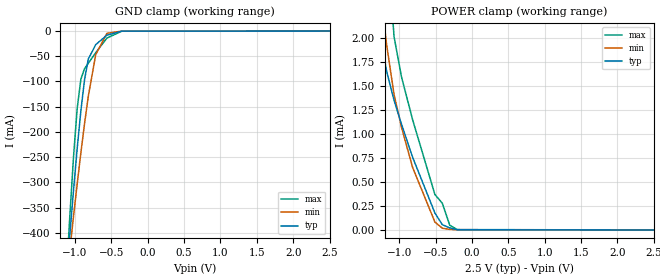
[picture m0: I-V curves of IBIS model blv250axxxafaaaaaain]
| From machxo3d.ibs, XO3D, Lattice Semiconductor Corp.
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|   Model blv250axxxafaaaaaain
[Model] blv250axxxafaaaaaain
Model_type Input
Polarity   Non-Inverting
Enable   Active-High
Vinl =  1.150V
Vinh =  1.350V
C_comp   4.200pF   3.800pF   7.500pF
[Temperature Range]   25.000   0.105k   -40.000
[Voltage Range]   2.500V   2.380V   2.630V
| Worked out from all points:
|   GND clamp passes 1 mA (typ) near -0.43 V on its own axis
|   POWER clamp passes 1 mA (typ) near -0.92 V on its own axis
[GND_clamp]
|Voltage   I(typ)   I(min)   I(max)
-2.5V     -3.262A    -2.545A    -4.485A
-1.123V   -498.5mA   -505.1mA   -498.3mA
-1.072V   -406.1mA   -436mA     -369.4mA
-1.021V   -317.1mA   -368.7mA   -251mA
-970mV    -233.3mA   -303.5mA   -153.4mA
-919mV    -157.7mA   -241.1mA   -95.21mA
-868mV    -95.78mA   -182.7mA   -74.26mA
-817mV    -55.48mA   -129.4mA   -63.96mA
-715mV    -26.89mA   -46.57mA   -42.82mA
-562mV    -8.195mA   -4.484mA   -13.98mA
-358mV    -153.4uA   -68.26uA   -250.2uA
2.5V      0A         0A         0A
[POWER_clamp]
|Voltage   I(typ)   I(min)   I(max)
-2.5V     19.37mA    14.08mA    35.47mA
-1.274V   2.185mA    2.634mA    5.424mA
-1.223V   1.865mA    2.265mA    4.051mA
-1.172V   1.654mA    1.93mA     3.052mA
-1.07V    1.353mA    1.412mA    2.016mA
-968mV    1.104mA    1.071mA    1.597mA
-815mV    758.5uA    651.8uA    1.15mA
-509mV    176.7uA    82.75uA    370.5uA
-407mV    55.24uA    18.01uA    278.8uA
-305mV    21.57uA    6.5uA      49.89uA
-203mV    2.401uA    2.25uA     4.21uA
2.5V      0A         0A         3.059nA
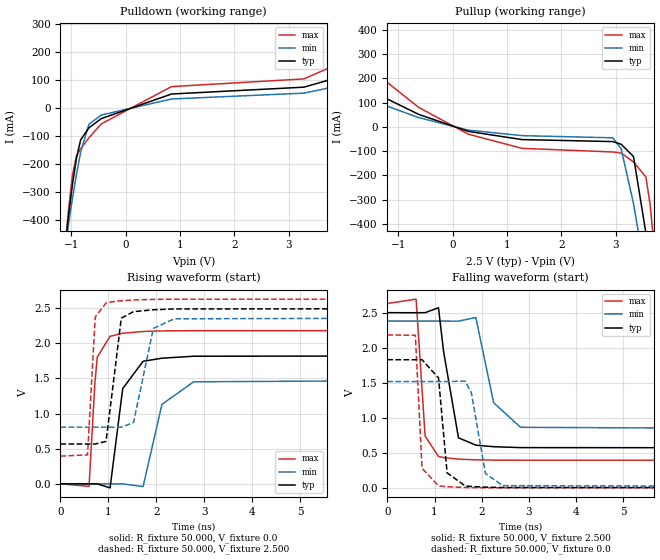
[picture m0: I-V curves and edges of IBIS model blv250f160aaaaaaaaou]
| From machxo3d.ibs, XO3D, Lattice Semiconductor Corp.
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|   Model blv250f160aaaaaaaaou
[Model] blv250f160aaaaaaaaou
Model_type Output
Polarity   Non-Inverting
Enable   Active-High
Vmeas =  1.250V
Cref =  3.000pF
Rref =  50.000
Vref =  1.250V
C_comp   4.200pF   3.800pF   7.500pF
[Temperature Range]   25.000   0.105k   -40.000
[Voltage Range]   2.500V   2.380V   2.630V
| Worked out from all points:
|   slope of the pulldown table from 0 to 0.375 V, typ, clamps not added: 13.6 ohm
|   slope of the pullup table from 0 to 0.375 V, typ, clamps not added: 16.3 ohm
|   rising waveform, R_fixture 50.000, V_fixture 0.0: 20-80 % time 206ps typ, 326ps min, 111ps max; typ from 0 V to 1.83 V
|   rising waveform, R_fixture 50.000, V_fixture 2.500: 20-80 % time 152ps typ, 261ps min, 82.5ps max; typ from 0.567 V to 2.5 V
|   falling waveform, R_fixture 50.000, V_fixture 2.500: 20-80 % time 196ps typ, 321ps min, 119ps max; typ from 2.5 V to 0.567 V
|   falling waveform, R_fixture 50.000, V_fixture 0.0: 20-80 % time 127ps typ, 212ps min, 78.8ps max; typ from 1.83 V to 0 V
[Pulldown]
|Voltage   I(typ)   I(min)   I(max)
-2.5V     -3.263A    -2.546A    -4.487A
-1.132V   -524.4mA   -522.1mA   -541.9mA
-1.056V   -391.7mA   -420.6mA   -371.7mA
-980mV    -273mA     -323.8mA   -240.3mA
-904mV    -177.6mA   -234.6mA   -169.5mA
-828mV    -113.5mA   -157.4mA   -146mA
-676mV    -70.67mA   -57.86mA   -106.2mA
-448mV    -37.92mA   -25.21mA   -56.63mA
844mV     49.74mA    32.02mA    76.15mA
3.276V    74.1mA     52.77mA    103.6mA
4.188V    124.4mA    89.67mA    180.5mA
5V        189.3mA    133.3mA    285.6mA
[Pullup]
|Voltage   I(typ)   I(min)   I(max)
-2.5V     258.3mA    191.7mA    416mA
-624mV    51.9mA     38.54mA    80.72mA
288mV     -18.29mA   -13.09mA   -29.66mA
1.276V    -52.17mA   -35.9mA    -88.36mA
2.948V    -60.45mA   -44.87mA   -103.4mA
3.1V      -71.47mA   -89.87mA   -107.6mA
3.328V    -122.2mA   -316.8mA   -144.4mA
3.556V    -438.5mA   -619.2mA   -206.7mA
3.632V    -576mA     -726.1mA   -318mA
3.708V    -718.7mA   -834.7mA   -491.1mA
3.784V    -864.6mA   -944.6mA   -687mA
5V        -3.326A    -2.771A    -4.212A
[Ramp]
| variable   typ   min   max
dV/dt_r   1.097/0.206n   0.910/0.325n   1.309/0.110n
dV/dt_f   1.160/0.196n   0.944/0.320n   1.341/0.119n
R_load = 50.000
[Rising Waveform]
R_fixture= 50.000
V_fixture= 0.0
V_fixture_min= 0.0
V_fixture_max= 0.0
|time   V(typ)   V(min)   V(max)
0s        6.258nV    42.73nV    18.47nV
597ps     -200.6uV   920.1nV    -35.25mV
718ps     -428.8uV   920.1nV    1.422V
769ps     -516.5uV   920.1nV    1.805V
1.036ns   -57.26mV   -22.87uV   2.101V
1.3ns     1.356V     -654.9uV   2.144V
1.725ns   1.745V     -39mV      2.169V
2.119ns   1.789V     1.132V     2.177V
2.781ns   1.817V     1.453V     2.181V
20ns      1.829V     1.517V     2.182V
[Rising Waveform]
R_fixture= 50.000
V_fixture= 2.500
V_fixture_min= 2.380
V_fixture_max= 2.630
|time   V(typ)   V(min)   V(max)
0s        567.4mV    806.9mV    394.6mV
565ps     567.2mV    806.9mV    412.4mV
727ps     567mV      806.9mV    2.377V
951ps     604.4mV    806.7mV    2.574V
1.068ns   1.238V     806.2mV    2.591V
1.27ns    2.359V     806.8mV    2.607V
1.525ns   2.452V     871.4mV    2.618V
1.939ns   2.478V     2.213V     2.626V
2.376ns   2.49V      2.35V      2.629V
20ns      2.5V       2.38V      2.63V
[Falling Waveform]
R_fixture= 50.000
V_fixture= 2.500
V_fixture_min= 2.380
V_fixture_max= 2.630
|time   V(typ)   V(min)   V(max)
0s        2.5V       2.38V      2.63V
610ps     2.499V     2.38V      2.693V
801ps     2.5V       2.38V      738.5mV
1.084ns   2.57V      2.38V      448mV
1.192ns   1.947V     2.38V      432.3mV
1.508ns   714mV      2.379V     410mV
1.876ns   609.5mV    2.431V     399.7mV
2.253ns   587.2mV    1.214V     396.2mV
2.823ns   574.3mV    864.2mV    394.9mV
20ns      567.3mV    806.9mV    394.5mV
[Falling Waveform]
R_fixture= 50.000
V_fixture= 0.0
V_fixture_min= 0.0
V_fixture_max= 0.0
|time   V(typ)   V(min)   V(max)
0s        1.829V     1.517V     2.182V
594ps     1.828V     1.517V     2.177V
736ps     1.829V     1.517V     278.8mV
1.085ns   1.568V     1.517V     29.01mV
1.267ns   213.9mV    1.517V     15.96mV
1.649ns   28.04mV    1.523V     5.319mV
1.782ns   19.34mV    1.354V     3.815mV
2.078ns   10.17mV    205.1mV    1.609mV
2.445ns   5.144mV    31.58mV    507.2uV
20ns      -109.5nV   -67.12nV   -21.07nV
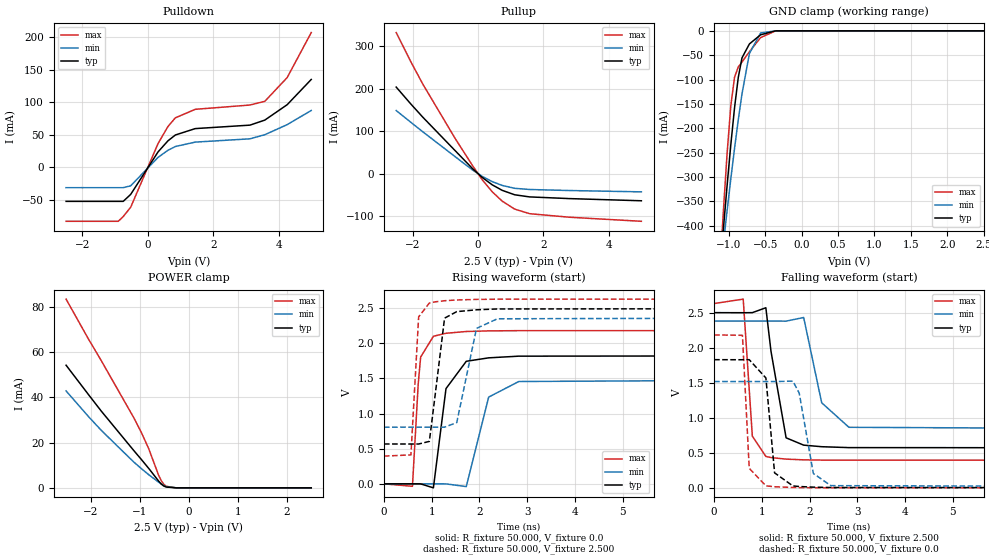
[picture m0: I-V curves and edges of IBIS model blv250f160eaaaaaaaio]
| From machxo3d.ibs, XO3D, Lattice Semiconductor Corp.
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|   Model blv250f160eaaaaaaaio
[Model] blv250f160eaaaaaaaio
Model_type I/O
Polarity   Non-Inverting
Enable   Active-Low
Vinl =  1.150V
Vinh =  1.350V
Vmeas =  1.250V
Cref =  3.000pF
Rref =  50.000
Vref =  1.250V
C_comp   4.200pF   3.800pF   7.500pF
[Temperature Range]   25.000   0.105k   -40.000
[Voltage Range]   2.500V   2.380V   2.630V
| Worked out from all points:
|   slope of the pulldown table from 0 to 0.375 V, typ, clamps not added: 13.6 ohm
|   slope of the pullup table from 0 to 0.375 V, typ, clamps not added: 16.3 ohm
|   GND clamp passes 1 mA (typ) near -0.43 V on its own axis
|   POWER clamp passes 1 mA (typ) near -0.52 V on its own axis
|   rising waveform, R_fixture 50.000, V_fixture 0.0: 20-80 % time 206ps typ, 326ps min, 111ps max; typ from 0 V to 1.83 V
|   rising waveform, R_fixture 50.000, V_fixture 2.500: 20-80 % time 152ps typ, 261ps min, 82.5ps max; typ from 0.567 V to 2.5 V
|   falling waveform, R_fixture 50.000, V_fixture 2.500: 20-80 % time 196ps typ, 321ps min, 119ps max; typ from 2.5 V to 0.567 V
|   falling waveform, R_fixture 50.000, V_fixture 0.0: 20-80 % time 127ps typ, 212ps min, 78.8ps max; typ from 1.83 V to 0 V
[Pulldown]
|Voltage   I(typ)   I(min)   I(max)
-2.5V     -52.31mA   -31.26mA   -82.98mA
-904mV    -52.31mA   -31.26mA   -82.98mA
-752mV    -52.31mA   -31.26mA   -75.68mA
-524mV    -41.64mA   -28.44mA   -61.36mA
312mV     23.61mA    15.21mA    36.41mA
616mV     40.73mA    26.21mA    62.71mA
844mV     49.74mA    32.02mA    76.15mA
1.452V    59.56mA    38.79mA    89.19mA
3.124V    64.87mA    43.83mA    95.79mA
3.58V     72.62mA    50.15mA    101.5mA
4.264V    96.31mA    65.66mA    138mA
5V        135.1mA    87.41mA    207.2mA
[Pullup]
|Voltage   I(typ)   I(min)   I(max)
-2.5V     204.1mA    148.8mA    332.6mA
-2.068V   165.6mA    122.1mA    266.1mA
-1.688V   133.3mA    98.85mA    211.4mA
-700mV    54.54mA    40.29mA    83.37mA
-168mV    12.23mA    8.92mA     19.44mA
136mV     -9.136mA   -6.562mA   -14.75mA
440mV     -26.35mA   -18.77mA   -42.94mA
744mV     -39.29mA   -27.7mA    -64.76mA
1.124V    -49.7mA    -34.48mA   -83.45mA
1.58V     -54.71mA   -37.23mA   -94.24mA
2.796V    -58.69mA   -39.68mA   -102.6mA
5V        -63.82mA   -42.81mA   -112.2mA
[GND_clamp]
|Voltage   I(typ)   I(min)   I(max)
-2.5V     -3.262A    -2.545A    -4.485A
-1.123V   -498.5mA   -505.1mA   -498.3mA
-1.072V   -406.1mA   -436mA     -369.4mA
-1.021V   -317.1mA   -368.7mA   -251mA
-970mV    -233.3mA   -303.5mA   -153.4mA
-919mV    -157.7mA   -241.1mA   -95.21mA
-868mV    -95.78mA   -182.7mA   -74.26mA
-817mV    -55.48mA   -129.4mA   -63.96mA
-715mV    -26.89mA   -46.57mA   -42.82mA
-562mV    -8.195mA   -4.484mA   -13.98mA
-358mV    -153.4uA   -68.26uA   -250.2uA
2.5V      0A         0A         0A
[POWER_clamp]
|Voltage   I(typ)   I(min)   I(max)
-2.5V     54.22mA    42.85mA    83.44mA
-2.039V   41.12mA    31.42mA    65.62mA
-1.784V   33.98mA    25.46mA    56.3mA
-1.121V   16.55mA    11.45mA    31.07mA
-968mV    12.63mA    8.576mA    24.62mA
-815mV    8.614mA    5.831mA    17.33mA
-611mV    2.953mA    2.495mA    5.465mA
-560mV    1.702mA    1.758mA    3.215mA
-509mV    833.1uA    1.093mA    1.608mA
-458mV    359uA      552.7uA    679.3uA
-254mV    7.444uA    6.928uA    15.57uA
2.5V      0A         0A         3.059nA
[Ramp]
| variable   typ   min   max
dV/dt_r   1.097/0.206n   0.910/0.325n   1.309/0.110n
dV/dt_f   1.160/0.196n   0.944/0.320n   1.341/0.119n
R_load = 50.000
[Rising Waveform]
R_fixture= 50.000
V_fixture= 0.0
V_fixture_min= 0.0
V_fixture_max= 0.0
|time   V(typ)   V(min)   V(max)
0s        6.258nV    42.86nV    18.47nV
597ps     -200.6uV   924.5nV    -35.25mV
718ps     -428.8uV   924.5nV    1.422V
769ps     -516.5uV   924.5nV    1.805V
1.036ns   -57.26mV   -22.86uV   2.101V
1.3ns     1.356V     -654.8uV   2.144V
1.725ns   1.745V     -39mV      2.169V
2.194ns   1.794V     1.235V     2.178V
2.825ns   1.818V     1.457V     2.181V
20ns      1.829V     1.517V     2.182V
[Rising Waveform]
R_fixture= 50.000
V_fixture= 2.500
V_fixture_min= 2.380
V_fixture_max= 2.630
|time   V(typ)   V(min)   V(max)
0s        567.4mV    806.9mV    394.6mV
565ps     567.2mV    806.9mV    412.4mV
727ps     567mV      806.9mV    2.377V
951ps     604.4mV    806.7mV    2.574V
1.068ns   1.238V     806.2mV    2.591V
1.27ns    2.359V     806.8mV    2.607V
1.525ns   2.452V     871.4mV    2.618V
1.939ns   2.478V     2.213V     2.626V
2.376ns   2.49V      2.35V      2.629V
20ns      2.5V       2.38V      2.63V
[Falling Waveform]
R_fixture= 50.000
V_fixture= 2.500
V_fixture_min= 2.380
V_fixture_max= 2.630
|time   V(typ)   V(min)   V(max)
0s        2.5V       2.38V      2.63V
610ps     2.499V     2.38V      2.693V
801ps     2.5V       2.38V      738.5mV
1.084ns   2.57V      2.38V      448mV
1.192ns   1.947V     2.38V      432.3mV
1.508ns   714mV      2.379V     410mV
1.876ns   609.5mV    2.431V     399.7mV
2.253ns   587.2mV    1.214V     396.2mV
2.823ns   574.3mV    864.2mV    394.9mV
20ns      567.3mV    806.9mV    394.5mV
[Falling Waveform]
R_fixture= 50.000
V_fixture= 0.0
V_fixture_min= 0.0
V_fixture_max= 0.0
|time   V(typ)   V(min)   V(max)
0s        1.829V     1.517V     2.182V
594ps     1.828V     1.517V     2.177V
736ps     1.829V     1.517V     278.8mV
1.085ns   1.568V     1.517V     29.01mV
1.267ns   213.9mV    1.517V     15.96mV
1.649ns   28.04mV    1.523V     5.319mV
1.782ns   19.34mV    1.354V     3.815mV
2.078ns   10.17mV    205.1mV    1.609mV
2.445ns   5.144mV    31.58mV    507.2uV
20ns      -109.5nV   -67.12nV   -21.07nV
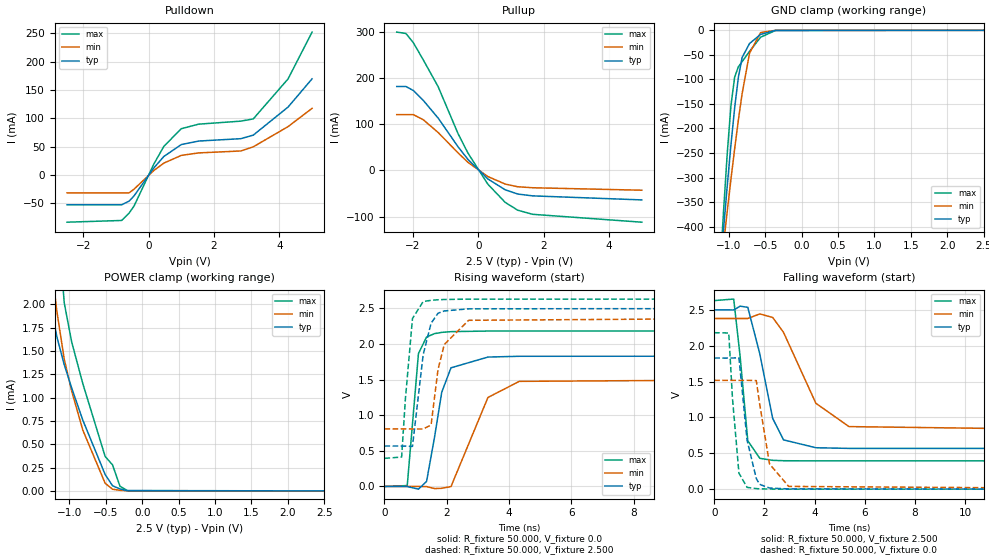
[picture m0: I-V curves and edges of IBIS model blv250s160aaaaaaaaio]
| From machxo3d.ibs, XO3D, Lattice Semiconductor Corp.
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|   Model blv250s160aaaaaaaaio
[Model] blv250s160aaaaaaaaio
Model_type I/O
Polarity   Non-Inverting
Enable   Active-Low
Vinl =  1.150V
Vinh =  1.350V
Vmeas =  1.250V
Cref =  3.000pF
Rref =  50.000
Vref =  1.250V
C_comp   4.200pF   3.800pF   7.500pF
[Temperature Range]   25.000   0.105k   -40.000
[Voltage Range]   2.500V   2.380V   2.630V
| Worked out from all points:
|   slope of the pulldown table from 0 to 0.375 V, typ, clamps not added: 13.6 ohm
|   slope of the pullup table from 0 to 0.375 V, typ, clamps not added: 16.3 ohm
|   GND clamp passes 1 mA (typ) near -0.43 V on its own axis
|   POWER clamp passes 1 mA (typ) near -0.92 V on its own axis
|   rising waveform, R_fixture 50.000, V_fixture 0.0: 20-80 % time 428ps typ, 783ps min, 212ps max; typ from 0 V to 1.83 V
|   rising waveform, R_fixture 50.000, V_fixture 2.500: 20-80 % time 387ps typ, 428ps min, 242ps max; typ from 0.567 V to 2.5 V
|   falling waveform, R_fixture 50.000, V_fixture 2.500: 20-80 % time 674ps typ, 1.31ns min, 338ps max; typ from 2.5 V to 0.567 V
|   falling waveform, R_fixture 50.000, V_fixture 0.0: 20-80 % time 439ps typ, 471ps min, 277ps max; typ from 1.83 V to 0 V
[Pulldown]
|Voltage   I(typ)   I(min)   I(max)
-2.5V     -52.31mA   -31.26mA   -82.98mA
-828mV    -52.31mA   -31.26mA   -79.94mA
-600mV    -45.86mA   -31.26mA   -66.93mA
-448mV    -36.56mA   -24.66mA   -54.4mA
160mV     12.89mA    8.306mA    19.88mA
464mV     32.88mA    21.18mA    50.69mA
996mV     53.81mA    34.73mA    81.8mA
1.528V    60.05mA    39.14mA    89.82mA
2.82V     64.22mA    42.56mA    95.13mA
3.2V      70.47mA    49.87mA    99.09mA
4.264V    119.9mA    85.45mA    169.5mA
5V        169.7mA    117.7mA    252.1mA
[Pullup]
|Voltage   I(typ)   I(min)   I(max)
-2.5V     182.4mA    121.2mA    300.4mA
-2.22V    182.4mA    121.2mA    297.4mA
-1.992V   173.6mA    121.2mA    277.4mA
-1.688V   152.2mA    110.2mA    240.1mA
-1.232V   113.7mA    82.42mA    181.8mA
-624mV    51.53mA    38.3mA     80.07mA
-320mV    23.99mA    17.67mA    37.75mA
288mV     -18.29mA   -13.09mA   -29.66mA
820mV     -41.87mA   -29.44mA   -69.24mA
1.2V      -51.05mA   -35.28mA   -86.08mA
1.656V    -55.06mA   -37.43mA   -95.07mA
5V        -63.82mA   -42.81mA   -112.2mA
[GND_clamp]
|Voltage   I(typ)   I(min)   I(max)
-2.5V     -3.262A    -2.545A    -4.485A
-1.123V   -498.5mA   -505.1mA   -498.3mA
-1.072V   -406.1mA   -436mA     -369.4mA
-1.021V   -317.1mA   -368.7mA   -251mA
-970mV    -233.3mA   -303.5mA   -153.4mA
-919mV    -157.7mA   -241.1mA   -95.21mA
-868mV    -95.78mA   -182.7mA   -74.26mA
-817mV    -55.48mA   -129.4mA   -63.96mA
-715mV    -26.89mA   -46.57mA   -42.82mA
-562mV    -8.195mA   -4.484mA   -13.98mA
-358mV    -153.4uA   -68.26uA   -250.2uA
2.5V      0A         0A         0A
[POWER_clamp]
|Voltage   I(typ)   I(min)   I(max)
-2.5V     19.37mA    14.08mA    35.47mA
-1.274V   2.185mA    2.634mA    5.424mA
-1.223V   1.865mA    2.265mA    4.051mA
-1.172V   1.654mA    1.93mA     3.052mA
-1.07V    1.353mA    1.412mA    2.016mA
-968mV    1.104mA    1.071mA    1.597mA
-815mV    758.5uA    651.8uA    1.15mA
-509mV    176.7uA    82.75uA    370.5uA
-407mV    55.24uA    18.01uA    278.8uA
-305mV    21.57uA    6.5uA      49.89uA
-203mV    2.401uA    2.25uA     4.21uA
2.5V      0A         0A         3.059nA
[Ramp]
| variable   typ   min   max
dV/dt_r   1.097/0.427n   0.910/0.781n   1.309/0.212n
dV/dt_f   1.160/0.674n   0.944/1.308n   1.341/0.338n
R_load = 50.000
[Rising Waveform]
R_fixture= 50.000
V_fixture= 0.0
V_fixture_min= 0.0
V_fixture_max= 0.0
|time   V(typ)   V(min)   V(max)
0s        6.258nV    42.67nV    18.47nV
731ps     -485.9uV   576.8nV    12.5mV
1.091ns   -38.02mV   -270.6uV   1.865V
1.352ns   70.76mV    -1.671mV   2.098V
1.607ns   689.8mV    -29.61mV   2.145V
1.839ns   1.323V     -26.03mV   2.162V
2.136ns   1.665V     -1.426mV   2.173V
3.323ns   1.816V     1.249V     2.181V
4.329ns   1.827V     1.475V     2.182V
20ns      1.829V     1.517V     2.182V
[Rising Waveform]
R_fixture= 50.000
V_fixture= 2.500
V_fixture_min= 2.380
V_fixture_max= 2.630
|time   V(typ)   V(min)   V(max)
0s        567.4mV    806.9mV    394.6mV
551ps     567.3mV    806.9mV    412.3mV
670ps     566.6mV    806.9mV    1.219V
899ps     562.6mV    806.9mV    2.358V
1.242ns   1.848V     806.7mV    2.594V
1.497ns   2.291V     862.1mV    2.613V
1.719ns   2.431V     1.642V     2.62V
1.921ns   2.463V     1.993V     2.624V
2.704ns   2.493V     2.332V     2.629V
20ns      2.5V       2.38V      2.63V
[Falling Waveform]
R_fixture= 50.000
V_fixture= 2.500
V_fixture_min= 2.380
V_fixture_max= 2.630
|time   V(typ)   V(min)   V(max)
0s        2.5V       2.38V      2.63V
777ps     2.499V     2.38V      2.651V
1.033ns   2.552V     2.38V      1.852V
1.338ns   2.536V     2.38V      675mV
1.817ns   1.887V     2.444V     430.3mV
2.328ns   988.7mV    2.395V     402.3mV
2.76ns    687.8mV    2.188V     396.6mV
4.05ns    577.7mV    1.198V     394.5mV
5.369ns   568.6mV    872.5mV    394.4mV
20ns      567.4mV    806.8mV    394.4mV
[Falling Waveform]
R_fixture= 50.000
V_fixture= 0.0
V_fixture_min= 0.0
V_fixture_max= 0.0
|time   V(typ)   V(min)   V(max)
0s        1.829V     1.517V     2.182V
580ps     1.828V     1.517V     2.178V
729ps     1.829V     1.517V     1.263V
986ps     1.833V     1.517V     224.2mV
1.31ns    684.8mV    1.518V     24.95mV
1.676ns   148.8mV    1.514V     7.802mV
1.811ns   67.29mV    1.187V     5.421mV
2.205ns   15.76mV    351.1mV    1.759mV
2.967ns   3.493mV    38.31mV    223.7uV
20ns      26.49nV    97.26nV    83.58nV
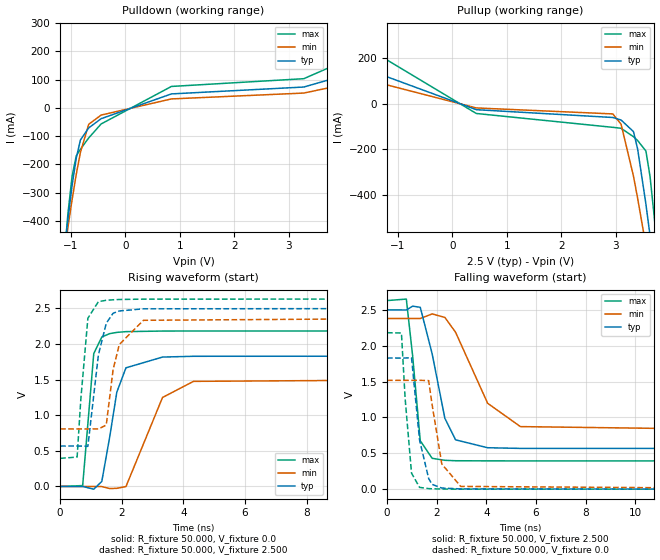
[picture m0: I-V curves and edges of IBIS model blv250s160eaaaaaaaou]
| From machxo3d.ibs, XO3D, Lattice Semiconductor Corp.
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|   Model blv250s160eaaaaaaaou
[Model] blv250s160eaaaaaaaou
Model_type Output
Polarity   Non-Inverting
Enable   Active-High
Vmeas =  1.250V
Cref =  3.000pF
Rref =  50.000
Vref =  1.250V
C_comp   4.200pF   3.800pF   7.500pF
[Temperature Range]   25.000   0.105k   -40.000
[Voltage Range]   2.500V   2.380V   2.630V
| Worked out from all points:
|   slope of the pulldown table from 0 to 0.375 V, typ, clamps not added: 13.6 ohm
|   slope of the pullup table from 0 to 0.375 V, typ, clamps not added: 16.3 ohm
|   rising waveform, R_fixture 50.000, V_fixture 0.0: 20-80 % time 428ps typ, 783ps min, 212ps max; typ from 0 V to 1.83 V
|   rising waveform, R_fixture 50.000, V_fixture 2.500: 20-80 % time 387ps typ, 428ps min, 243ps max; typ from 0.567 V to 2.5 V
|   falling waveform, R_fixture 50.000, V_fixture 2.500: 20-80 % time 674ps typ, 1.31ns min, 338ps max; typ from 2.5 V to 0.567 V
|   falling waveform, R_fixture 50.000, V_fixture 0.0: 20-80 % time 439ps typ, 471ps min, 277ps max; typ from 1.83 V to 0 V
[Pulldown]
|Voltage   I(typ)   I(min)   I(max)
-2.5V     -3.263A    -2.546A    -4.487A
-1.132V   -524.4mA   -522.1mA   -541.9mA
-1.056V   -391.7mA   -420.6mA   -371.7mA
-980mV    -273mA     -323.8mA   -240.3mA
-904mV    -177.6mA   -234.6mA   -169.5mA
-828mV    -113.5mA   -157.4mA   -146mA
-676mV    -70.67mA   -57.86mA   -106.2mA
-448mV    -37.92mA   -25.21mA   -56.63mA
844mV     49.74mA    32.02mA    76.15mA
3.276V    74.1mA     52.77mA    103.6mA
4.188V    124.4mA    89.63mA    180.5mA
5V        189.1mA    133.2mA    285.3mA
[Pullup]
|Voltage   I(typ)   I(min)   I(max)
-2.5V     198.2mA    130.5mA    332.2mA
-1.992V   186.5mA    130.1mA    303.4mA
440mV     -26.35mA   -18.77mA   -42.94mA
2.948V    -60.45mA   -44.87mA   -103.4mA
3.1V      -71.47mA   -89.87mA   -107.6mA
3.328V    -122.2mA   -316.8mA   -144.4mA
3.404V    -198.1mA   -413.3mA   -161mA
3.556V    -438.5mA   -619.2mA   -206.7mA
3.632V    -576mA     -726.1mA   -318mA
3.708V    -718.7mA   -834.7mA   -491.1mA
3.784V    -864.6mA   -944.6mA   -687mA
5V        -3.326A    -2.771A    -4.212A
[Ramp]
| variable   typ   min   max
dV/dt_r   1.097/0.427n   0.910/0.781n   1.309/0.212n
dV/dt_f   1.160/0.674n   0.944/1.308n   1.341/0.338n
R_load = 50.000
[Rising Waveform]
R_fixture= 50.000
V_fixture= 0.0
V_fixture_min= 0.0
V_fixture_max= 0.0
|time   V(typ)   V(min)   V(max)
0s        6.258nV    42.67nV    18.47nV
731ps     -485.9uV   577.8nV    12.5mV
1.091ns   -38.02mV   -270.6uV   1.865V
1.352ns   70.76mV    -1.671mV   2.098V
1.607ns   689.8mV    -29.34mV   2.145V
1.839ns   1.323V     -26.03mV   2.162V
2.136ns   1.665V     -1.426mV   2.173V
3.323ns   1.816V     1.249V     2.181V
4.329ns   1.827V     1.475V     2.182V
20ns      1.829V     1.517V     2.182V
[Rising Waveform]
R_fixture= 50.000
V_fixture= 2.500
V_fixture_min= 2.380
V_fixture_max= 2.630
|time   V(typ)   V(min)   V(max)
0s        567.4mV    806.9mV    394.6mV
551ps     567.3mV    806.9mV    412.3mV
670ps     566.6mV    806.9mV    1.219V
900ps     563.1mV    806.9mV    2.361V
1.242ns   1.848V     806.7mV    2.594V
1.497ns   2.291V     862.1mV    2.613V
1.719ns   2.431V     1.642V     2.62V
1.921ns   2.463V     1.993V     2.624V
2.704ns   2.493V     2.332V     2.629V
20ns      2.5V       2.38V      2.63V
[Falling Waveform]
R_fixture= 50.000
V_fixture= 2.500
V_fixture_min= 2.380
V_fixture_max= 2.630
|time   V(typ)   V(min)   V(max)
0s        2.5V       2.38V      2.63V
777ps     2.499V     2.38V      2.651V
1.033ns   2.552V     2.38V      1.852V
1.338ns   2.536V     2.38V      675mV
1.817ns   1.887V     2.444V     430.3mV
2.328ns   988.7mV    2.395V     402.3mV
2.76ns    687.8mV    2.188V     396.6mV
4.05ns    577.7mV    1.198V     394.5mV
5.369ns   568.6mV    872.5mV    394.4mV
20ns      567.4mV    806.8mV    394.4mV
[Falling Waveform]
R_fixture= 50.000
V_fixture= 0.0
V_fixture_min= 0.0
V_fixture_max= 0.0
|time   V(typ)   V(min)   V(max)
0s        1.829V     1.517V     2.182V
580ps     1.828V     1.517V     2.178V
729ps     1.829V     1.517V     1.263V
986ps     1.833V     1.517V     224.2mV
1.31ns    684.8mV    1.518V     24.95mV
1.676ns   148.8mV    1.514V     7.802mV
1.811ns   67.29mV    1.187V     5.421mV
2.205ns   15.76mV    351.1mV    1.759mV
2.967ns   3.493mV    38.31mV    223.7uV
20ns      26.49nV    97.26nV    83.58nV
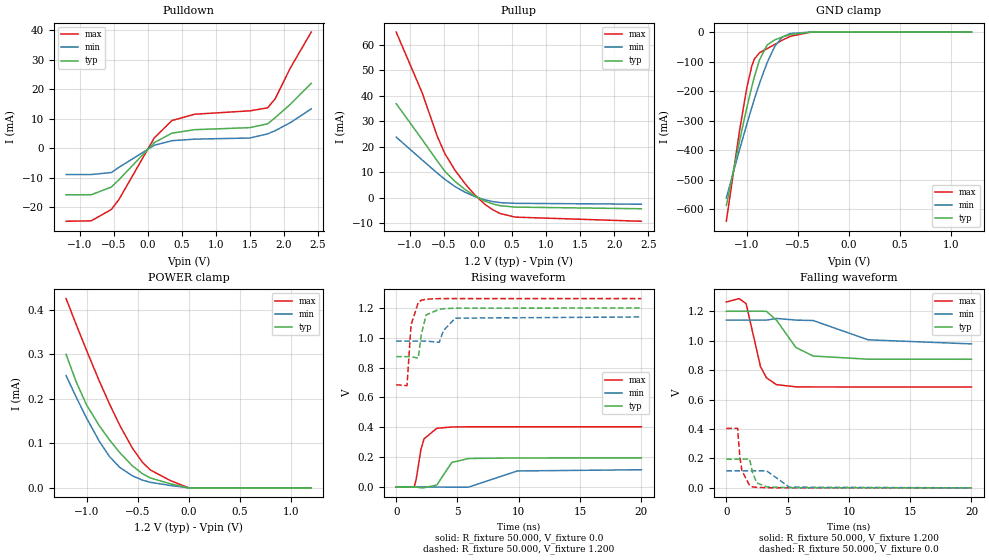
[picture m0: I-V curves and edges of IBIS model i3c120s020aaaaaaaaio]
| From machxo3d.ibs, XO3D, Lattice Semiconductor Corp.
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|   Model i3c120s020aaaaaaaaio
[Model] i3c120s020aaaaaaaaio
Model_type I/O
Polarity   Non-Inverting
Enable   Active-Low
Vinl =  0.420V
Vinh =  0.780V
Vmeas =  0.600V
Cref =  0.0F
Rref =  1.000M
Vref =  0.0V
C_comp   4.200pF   3.800pF   7.500pF
[Temperature Range]   25.000   0.105k   -40.000
[Voltage Range]   1.200V   1.140V   1.260V
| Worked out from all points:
|   slope of the pulldown table from 0 to 0.18 V, typ, clamps not added: 55.1 ohm
|   slope of the pullup table from 0 to 0.18 V, typ, clamps not added: 85.3 ohm
|   GND clamp passes 1 mA (typ) near -0.44 V on its own axis
|   rising waveform, R_fixture 50.000, V_fixture 0.0: 20-80 % time 910ps typ, 1.64ns min, 583ps max; typ from 0 V to 0.195 V
|   rising waveform, R_fixture 50.000, V_fixture 1.200: 20-80 % time 368ps typ, 414ps min, 384ps max; typ from 0.874 V to 1.2 V
|   falling waveform, R_fixture 50.000, V_fixture 1.200: 20-80 % time 1.84ns typ, 3.15ns min, 991ps max; typ from 1.2 V to 0.874 V
|   falling waveform, R_fixture 50.000, V_fixture 0.0: 20-80 % time 404ps typ, 468ps min, 389ps max; typ from 0.195 V to 0 V
[Pulldown]
|Voltage   I(typ)   I(min)   I(max)
-1.2V     -15.77mA   -8.921mA   -24.76mA
-830mV    -15.77mA   -8.921mA   -24.61mA
-534mV    -13.14mA   -8.234mA   -20.74mA
-423mV    -10.67mA   -6.463mA   -17.35mA
95mV      1.91mA     997.3uA    3.496mA
354mV     5.095mA    2.558mA    9.38mA
687mV     6.287mA    3.08mA     11.52mA
1.501V    6.983mA    3.463mA    12.68mA
1.76V     8.276mA    4.869mA    13.69mA
1.871V    10.37mA    5.955mA    16.78mA
2.093V    14.88mA    8.68mA     27.18mA
2.4V      22.01mA    13.33mA    39.38mA
[Pullup]
|Voltage   I(typ)   I(min)   I(max)
-1.2V     36.87mA    23.76mA    64.96mA
-819mV    22.8mA     14.8mA     41.13mA
-597mV    14.41mA    9.656mA    24.1mA
-486mV    10.37mA    7.225mA    17.3mA
-338mV    6.412mA    4.38mA     10.82mA
-190mV    3.229mA    2.154mA    5.518mA
-42mV     628.1uA    407.3uA    979.6uA
106mV     -1.356mA   -861.5uA   -2.669mA
217mV     -2.425mA   -1.522mA   -4.729mA
328mV     -3.145mA   -1.941mA   -6.218mA
550mV     -3.688mA   -2.208mA   -7.621mA
2.4V      -4.336mA   -2.551mA   -9.246mA
[GND_clamp]
|Voltage   I(typ)   I(min)   I(max)
-1.2V     -586.8mA   -561.6mA   -640.3mA
-1.075V   -375.3mA   -403.2mA   -342.9mA
-1V       -256.8mA   -312.3mA   -188.8mA
-950mV    -184.3mA   -254.5mA   -114mA
-925mV    -151.1mA   -226.6mA   -91.27mA
-875mV    -93.95mA   -173.6mA   -70mA
-800mV    -43.51mA   -102.9mA   -56.05mA
-725mV    -26.4mA    -48.03mA   -41.58mA
-650mV    -16.51mA   -16.35mA   -27.17mA
-575mV    -8.674mA   -5.016mA   -14.71mA
-375mV    -194.8uA   -87.66uA   -296.2uA
1.2V      -42.59nA   0A         -5.33uA
[POWER_clamp]
|Voltage   I(typ)   I(min)   I(max)
-1.2V     299.6uA    251.9uA    424.8uA
-1.1V     237.3uA    203.2uA    366uA
-1V       186.4uA    156.9uA    308.7uA
-875mV    139.5uA    104.5uA    239.9uA
-775mV    107.7uA    70.18uA    188.3uA
-675mV    79.18uA    45.9uA     140.6uA
-550mV    49.19uA    26.84uA    88.83uA
-450mV    31.3uA     17.16uA    56.66uA
-375mV    22.16uA    12.38uA    40.11uA
-175mV    8.775uA    5.159uA    15.8uA
0V        3.648nA    7.361nA    0A
1.2V      0A         0A         0A
[Ramp]
| variable   typ   min   max
dV/dt_r   0.117/0.904n   69.347m/1.658n   0.242/0.588n
dV/dt_f   0.196/1.819n   97.061m/3.123n   0.345/0.973n
R_load = 50.000
[Rising Waveform]
R_fixture= 50.000
V_fixture= 0.0
V_fixture_min= 0.0
V_fixture_max= 0.0
|time   V(typ)   V(min)   V(max)
0s        284.9uV    165.7uV    490.2uV
1.467ns   305.6uV    180.4uV    1.089mV
1.625ns   -392.5uV   180.4uV    49.23mV
2.016ns   -5.636mV   205.4uV    251.4mV
2.27ns    -5.071mV   346.2uV    322.7mV
3.309ns   13.22mV    -248.4uV   393.4mV
4.532ns   164.3mV    -1.2mV     402.4mV
5.901ns   191.1mV    -859.4uV   403.6mV
9.887ns   194.8mV    107.5mV    403.7mV
20ns      194.9mV    115.7mV    403.7mV
[Rising Waveform]
R_fixture= 50.000
V_fixture= 1.200
V_fixture_min= 1.140
V_fixture_max= 1.260
|time   V(typ)   V(min)   V(max)
0s        873.8mV    978mV      685.5mV
883ps     873.9mV    978mV      679.3mV
1.21ns    873.7mV    978mV      1.086V
1.799ns   864.2mV    978mV      1.237V
2.051ns   1.024V     977.9mV    1.252V
2.443ns   1.154V     977.9mV    1.259V
3.513ns   1.191V     970.1mV    1.263V
3.85ns    1.195V     1.048V     1.263V
4.815ns   1.199V     1.132V     1.263V
20ns      1.2V       1.14V      1.263V
[Falling Waveform]
R_fixture= 50.000
V_fixture= 1.200
V_fixture_min= 1.140
V_fixture_max= 1.260
|time   V(typ)   V(min)   V(max)
0s        1.2V       1.14V      1.263V
1.039ns   1.2V       1.14V      1.286V
1.612ns   1.2V       1.14V      1.252V
2.787ns   1.201V     1.14V      823.6mV
3.278ns   1.199V     1.14V      747.3mV
4.097ns   1.139V     1.151V     701.1mV
5.666ns   954.6mV    1.14V      686.6mV
7.086ns   895.8mV    1.137V     685.7mV
11.57ns   874.2mV    1.006V     685.5mV
20ns      873.8mV    978.2mV    685.5mV
[Falling Waveform]
R_fixture= 50.000
V_fixture= 0.0
V_fixture_min= 0.0
V_fixture_max= 0.0
|time   V(typ)   V(min)   V(max)
0s        194.9mV    115.8mV    403.7mV
915ps     195mV      115.8mV    405mV
1.109ns   195mV      115.8mV    208.1mV
1.267ns   194.8mV    115.8mV    117.8mV
1.891ns   196.9mV    115.8mV    16.47mV
2.135ns   106.1mV    115.8mV    7.102mV
2.483ns   33.6mV     115.7mV    3.016mV
3.289ns   6.717mV    115.6mV    918.7uV
5.14ns    973.3uV    4.592mV    512.3uV
20ns      284.9uV    166.6uV    490.1uV
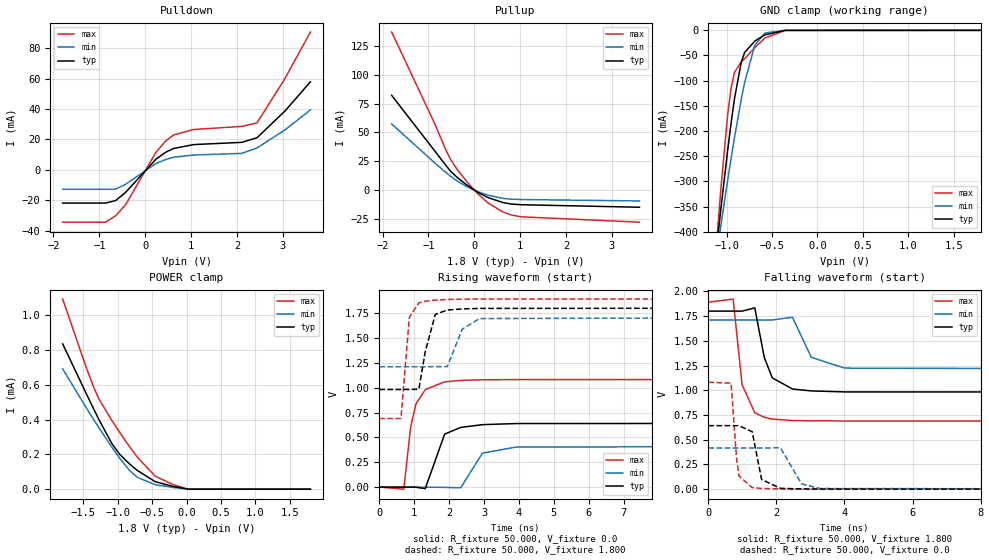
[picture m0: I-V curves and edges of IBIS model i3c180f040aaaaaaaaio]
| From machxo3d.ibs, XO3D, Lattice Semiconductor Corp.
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|   Model i3c180f040aaaaaaaaio
[Model] i3c180f040aaaaaaaaio
Model_type I/O
Polarity   Non-Inverting
Enable   Active-Low
Vinl =  0.630V
Vinh =  1.170V
Vmeas =  0.900V
Cref =  0.0F
Rref =  1.000M
Vref =  0.0V
C_comp   4.200pF   3.800pF   7.500pF
[Temperature Range]   25.000   0.105k   -40.000
[Voltage Range]   1.800V   1.710V   1.890V
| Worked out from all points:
|   slope of the pulldown table from 0 to 0.27 V, typ, clamps not added: 34 ohm
|   slope of the pullup table from 0 to 0.27 V, typ, clamps not added: 45.6 ohm
|   GND clamp passes 1 mA (typ) near -0.44 V on its own axis
|   rising waveform, R_fixture 50.000, V_fixture 0.0: 20-80 % time 385ps typ, 449ps min, 304ps max; typ from 0.001 V to 0.642 V
|   rising waveform, R_fixture 50.000, V_fixture 1.800: 20-80 % time 236ps typ, 364ps min, 142ps max; typ from 0.981 V to 1.8 V
|   falling waveform, R_fixture 50.000, V_fixture 1.800: 20-80 % time 355ps typ, 442ps min, 281ps max; typ from 1.8 V to 0.981 V
|   falling waveform, R_fixture 50.000, V_fixture 0.0: 20-80 % time 193ps typ, 338ps min, 125ps max; typ from 0.642 V to 0.001 V
[Pulldown]
|Voltage   I(typ)   I(min)   I(max)
-1.8V     -21.78mA   -12.65mA   -34.34mA
-865mV    -21.78mA   -12.65mA   -34.34mA
-645mV    -20.15mA   -12.65mA   -30.11mA
-425mV    -14.65mA   -9.378mA   -22.7mA
235mV     7.083mA    4.214mA    11.64mA
455mV     11.78mA    6.962mA    19.3mA
620mV     14.1mA     8.304mA    22.95mA
1.06V     16.63mA    9.799mA    26.56mA
2.105V    18.09mA    10.84mA    28.56mA
2.435V    21.1mA     14.39mA    30.83mA
3.04V     38.49mA    26.16mA    59.76mA
3.6V      57.85mA    39.38mA    90.5mA
[Pullup]
|Voltage   I(typ)   I(min)   I(max)
-1.8V     82.06mA    57.25mA    136.9mA
-855mV    33.62mA    23.37mA    56.89mA
-635mV    22.25mA    15.87mA    36.15mA
-525mV    16.78mA    12.26mA    27.16mA
-360mV    10.56mA    7.513mA    17.17mA
-140mV    3.787mA    2.633mA    6.305mA
80mV      -1.961mA   -1.338mA   -3.329mA
300mV     -6.456mA   -4.362mA   -11.09mA
630mV     -10.81mA   -7.147mA   -19.03mA
795mV     -11.95mA   -7.796mA   -21.4mA
1.015V    -12.62mA   -8.118mA   -23.07mA
3.6V      -14.81mA   -9.37mA    -27.75mA
[GND_clamp]
|Voltage   I(typ)   I(min)   I(max)
-1.8V     -1.677A    -1.372A    -2.207A
-1.097V   -411.6mA   -430.5mA   -393mA
-1.06V    -351mA     -384.7mA   -309.9mA
-986mV    -235.9mA   -295.9mA   -164.7mA
-949mV    -183mA     -253.4mA   -113mA
-912mV    -135mA     -212.5mA   -83.35mA
-838mV    -63.17mA   -137.2mA   -62.69mA
-801mV    -43.94mA   -103.8mA   -56.28mA
-690mV    -21.51mA   -30.07mA   -34.75mA
-579mV    -9.065mA   -5.356mA   -15.35mA
-357mV    -147.5uA   -72.3uA    -237.1uA
1.8V      -12.41nA   0A         -10.91uA
[POWER_clamp]
|Voltage   I(typ)   I(min)   I(max)
-1.8V     836.1uA    692.5uA    1.094mA
-1.456V   549uA      467.8uA    698.7uA
-1.345V   458uA      397.8uA    582.4uA
-1.271V   398.7uA    352uA      517.3uA
-1.086V   262.9uA    241.7uA    395.6uA
-975mV    202uA      179.8uA    328.7uA
-827mV    144.5uA    107.4uA    243.8uA
-716mV    108uA      68.49uA    184.9uA
-457mV    43.42uA    25.76uA    75.17uA
-198mV    15.77uA    10.09uA    26.67uA
24mV      0A         0A         0A
1.8V      0A         0A         0A
[Ramp]
| variable   typ   min   max
dV/dt_r   0.385/0.386n   0.249/0.445n   0.648/0.306n
dV/dt_f   0.491/0.348n   0.300/0.435n   0.720/0.280n
R_load = 50.000
[Rising Waveform]
R_fixture= 50.000
V_fixture= 0.0
V_fixture_min= 0.0
V_fixture_max= 0.0
|time   V(typ)   V(min)   V(max)
0s        714.8uV    493.6uV    1.055mV
699ps     759.9uV    520.7uV    -19.82mV
902ps     866.5uV    520.7uV    615mV
1.053ns   -645.3uV   495.7uV    838.4mV
1.316ns   -14.52mV   609.6uV    980.5mV
1.871ns   532.8mV    -1.877mV   1.058V
2.33ns    600.6mV    -6.567mV   1.073V
2.955ns   628.2mV    342mV      1.079V
3.905ns   639.2mV    402.6mV    1.081V
20ns      642.4mV    416.2mV    1.081V
[Rising Waveform]
R_fixture= 50.000
V_fixture= 1.800
V_fixture_min= 1.710
V_fixture_max= 1.890
|time   V(typ)   V(min)   V(max)
0s        981.3mV    1.21V      690.2mV
620ps     981.3mV    1.21V      690.3mV
861ps     982.1mV    1.21V      1.706V
1.133ns   984.2mV    1.21V      1.852V
1.315ns   1.36V      1.21V      1.868V
1.604ns   1.736V     1.211V     1.88V
1.95ns    1.78V      1.212V     1.886V
2.376ns   1.791V     1.588V     1.889V
2.87ns    1.796V     1.694V     1.89V
20ns      1.8V       1.71V      1.89V
[Falling Waveform]
R_fixture= 50.000
V_fixture= 1.800
V_fixture_min= 1.710
V_fixture_max= 1.890
|time   V(typ)   V(min)   V(max)
0s        1.8V       1.71V      1.89V
727ps     1.8V       1.71V      1.922V
991ps     1.8V       1.71V      1.056V
1.364ns   1.833V     1.71V      772.9mV
1.643ns   1.331V     1.709V     726.7mV
1.878ns   1.126V     1.711V     708.8mV
2.471ns   1.013V     1.738V     694.1mV
3.025ns   993.6mV    1.333V     691.7mV
4.005ns   983.6mV    1.224V     690.3mV
20ns      981.3mV    1.21V      690.1mV
[Falling Waveform]
R_fixture= 50.000
V_fixture= 0.0
V_fixture_min= 0.0
V_fixture_max= 0.0
|time   V(typ)   V(min)   V(max)
0s        642.4mV    416.2mV    1.081V
667ps     642.5mV    416.1mV    1.072V
829ps     642.4mV    416.2mV    309.4mV
898ps     642.2mV    416.2mV    134.6mV
1.288ns   581.3mV    416.2mV    16.2mV
1.565ns   98.02mV    416mV      7.937mV
2.116ns   8.922mV    419.7mV    2.498mV
2.738ns   3.095mV    53.87mV    1.371mV
3.284ns   1.52mV     7.108mV    1.13mV
20ns      714.7uV    493.5uV    1.054mV
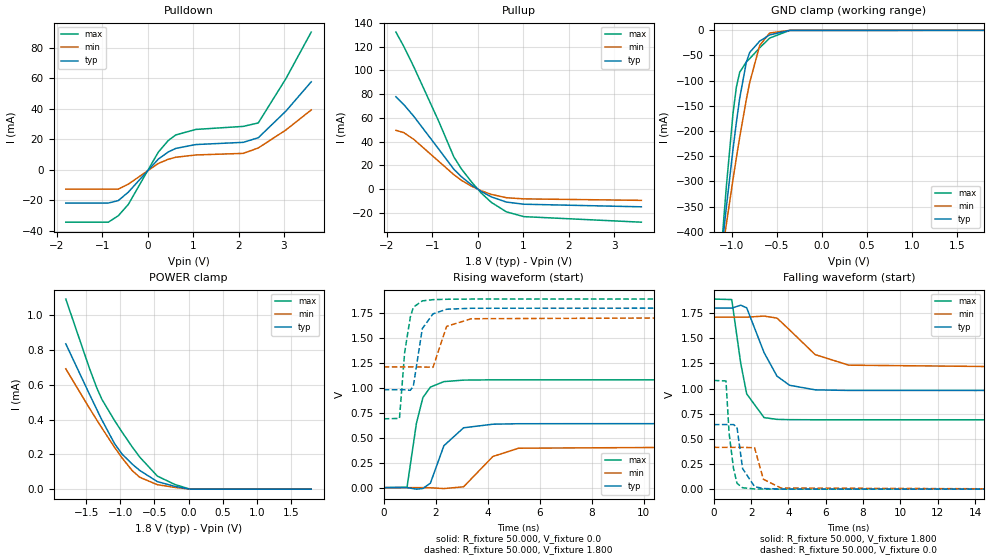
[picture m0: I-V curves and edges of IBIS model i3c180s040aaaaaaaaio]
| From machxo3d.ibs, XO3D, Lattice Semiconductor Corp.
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|   Model i3c180s040aaaaaaaaio
[Model] i3c180s040aaaaaaaaio
Model_type I/O
Polarity   Non-Inverting
Enable   Active-Low
Vinl =  0.630V
Vinh =  1.170V
Vmeas =  0.900V
Cref =  0.0F
Rref =  1.000M
Vref =  0.0V
C_comp   4.200pF   3.800pF   7.500pF
[Temperature Range]   25.000   0.105k   -40.000
[Voltage Range]   1.800V   1.710V   1.890V
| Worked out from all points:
|   slope of the pulldown table from 0 to 0.27 V, typ, clamps not added: 34 ohm
|   slope of the pullup table from 0 to 0.27 V, typ, clamps not added: 45.6 ohm
|   GND clamp passes 1 mA (typ) near -0.44 V on its own axis
|   rising waveform, R_fixture 50.000, V_fixture 0.0: 20-80 % time 628ps typ, 951ps min, 411ps max; typ from 0.001 V to 0.642 V
|   rising waveform, R_fixture 50.000, V_fixture 1.800: 20-80 % time 362ps typ, 366ps min, 303ps max; typ from 0.981 V to 1.8 V
|   falling waveform, R_fixture 50.000, V_fixture 1.800: 20-80 % time 1.1ns typ, 1.76ns min, 625ps max; typ from 1.8 V to 0.981 V
|   falling waveform, R_fixture 50.000, V_fixture 0.0: 20-80 % time 386ps typ, 404ps min, 327ps max; typ from 0.642 V to 0.001 V
[Pulldown]
|Voltage   I(typ)   I(min)   I(max)
-1.8V     -21.78mA   -12.65mA   -34.34mA
-865mV    -21.78mA   -12.65mA   -34.34mA
-645mV    -20.15mA   -12.65mA   -30.11mA
-425mV    -14.65mA   -9.378mA   -22.7mA
235mV     7.083mA    4.214mA    11.64mA
455mV     11.78mA    6.962mA    19.3mA
620mV     14.1mA     8.304mA    22.95mA
1.06V     16.63mA    9.799mA    26.56mA
2.105V    18.09mA    10.84mA    28.56mA
2.435V    21.1mA     14.39mA    30.83mA
3.04V     38.49mA    26.15mA    59.76mA
3.6V      57.82mA    39.35mA    90.47mA
[Pullup]
|Voltage   I(typ)   I(min)   I(max)
-1.8V     77.88mA    49.62mA    132.3mA
-1.625V   71.2mA     47.6mA     120.1mA
-1.405V   61.29mA    41.94mA    102.9mA
-855mV    33.62mA    23.37mA    56.89mA
-525mV    16.78mA    12.26mA    27.16mA
-360mV    10.56mA    7.513mA    17.17mA
-140mV    3.787mA    2.633mA    6.305mA
80mV      -1.961mA   -1.338mA   -3.329mA
300mV     -6.456mA   -4.362mA   -11.09mA
630mV     -10.81mA   -7.147mA   -19.03mA
1.015V    -12.62mA   -8.118mA   -23.07mA
3.6V      -14.81mA   -9.369mA   -27.75mA
[GND_clamp]
|Voltage   I(typ)   I(min)   I(max)
-1.8V     -1.677A    -1.372A    -2.207A
-1.097V   -411.6mA   -430.5mA   -393mA
-1.06V    -351mA     -384.7mA   -309.9mA
-986mV    -235.9mA   -295.9mA   -164.7mA
-949mV    -183mA     -253.4mA   -113mA
-912mV    -135mA     -212.5mA   -83.35mA
-838mV    -63.17mA   -137.2mA   -62.69mA
-801mV    -43.94mA   -103.8mA   -56.28mA
-690mV    -21.51mA   -30.07mA   -34.75mA
-579mV    -9.065mA   -5.356mA   -15.35mA
-357mV    -147.5uA   -72.3uA    -237.1uA
1.8V      -12.41nA   0A         -10.91uA
[POWER_clamp]
|Voltage   I(typ)   I(min)   I(max)
-1.8V     836.1uA    692.5uA    1.094mA
-1.456V   549uA      467.8uA    698.7uA
-1.345V   458uA      397.8uA    582.4uA
-1.271V   398.7uA    352uA      517.3uA
-1.086V   262.9uA    241.7uA    395.6uA
-975mV    202uA      179.8uA    328.7uA
-827mV    144.5uA    107.4uA    243.8uA
-716mV    108uA      68.49uA    184.9uA
-457mV    43.42uA    25.76uA    75.17uA
-198mV    15.77uA    10.09uA    26.67uA
24mV      0A         0A         0A
1.8V      0A         0A         0A
[Ramp]
| variable   typ   min   max
dV/dt_r   0.385/0.631n   0.249/0.940n   0.648/0.409n
dV/dt_f   0.491/1.089n   0.300/1.762n   0.720/0.623n
R_load = 50.000
[Rising Waveform]
R_fixture= 50.000
V_fixture= 0.0
V_fixture_min= 0.0
V_fixture_max= 0.0
|time   V(typ)   V(min)   V(max)
0s        714.8uV    493.6uV    1.055mV
899ps     706.8uV    520.4uV    5.309mV
1.26ns    -14.58mV   610.1uV    646.2mV
1.509ns   -7.692mV   672.9uV    902.9mV
1.796ns   45.2mV     -677.6uV   1.008V
2.316ns   420.7mV    -8.747mV   1.063V
3.072ns   600.2mV    9.105mV    1.078V
4.2ns     636.3mV    312.9mV    1.081V
5.189ns   641.1mV    395.8mV    1.081V
20ns      642.4mV    416.2mV    1.081V
[Rising Waveform]
R_fixture= 50.000
V_fixture= 1.800
V_fixture_min= 1.710
V_fixture_max= 1.890
|time   V(typ)   V(min)   V(max)
0s        981.3mV    1.21V      690.2mV
608ps     981.3mV    1.21V      694.3mV
807ps     981.3mV    1.21V      1.354V
1.024ns   975.8mV    1.21V      1.708V
1.141ns   1.017V     1.21V      1.808V
1.486ns   1.594V     1.21V      1.872V
1.898ns   1.742V     1.206V     1.884V
2.422ns   1.788V     1.617V     1.888V
3.369ns   1.798V     1.693V     1.89V
20ns      1.8V       1.71V      1.89V
[Falling Waveform]
R_fixture= 50.000
V_fixture= 1.800
V_fixture_min= 1.710
V_fixture_max= 1.890
|time   V(typ)   V(min)   V(max)
0s        1.8V       1.71V      1.89V
963ps     1.8V       1.71V      1.885V
1.445ns   1.829V     1.71V      1.251V
1.765ns   1.803V     1.71V      947.3mV
2.695ns   1.358V     1.721V     711.9mV
3.388ns   1.124V     1.701V     694.2mV
4.065ns   1.033V     1.583V     691.2mV
5.433ns   987.7mV    1.338V     690.2mV
7.235ns   981.7mV    1.233V     690.2mV
20ns      981.3mV    1.21V      690.2mV
[Falling Waveform]
R_fixture= 50.000
V_fixture= 0.0
V_fixture_min= 0.0
V_fixture_max= 0.0
|time   V(typ)   V(min)   V(max)
0s        642.4mV    416.2mV    1.081V
654ps     642.5mV    416.2mV    1.076V
823ps     642.4mV    416.2mV    553.8mV
1.058ns   642.4mV    416.2mV    206.1mV
1.245ns   615.9mV    416.2mV    58.8mV
1.544ns   205.5mV    416mV      14.32mV
2.187ns   25.49mV    412.1mV    2.881mV
2.656ns   7.175mV    99.06mV    1.563mV
3.597ns   1.75mV     12.08mV    1.107mV
20ns      714.8uV    493.6uV    1.055mV
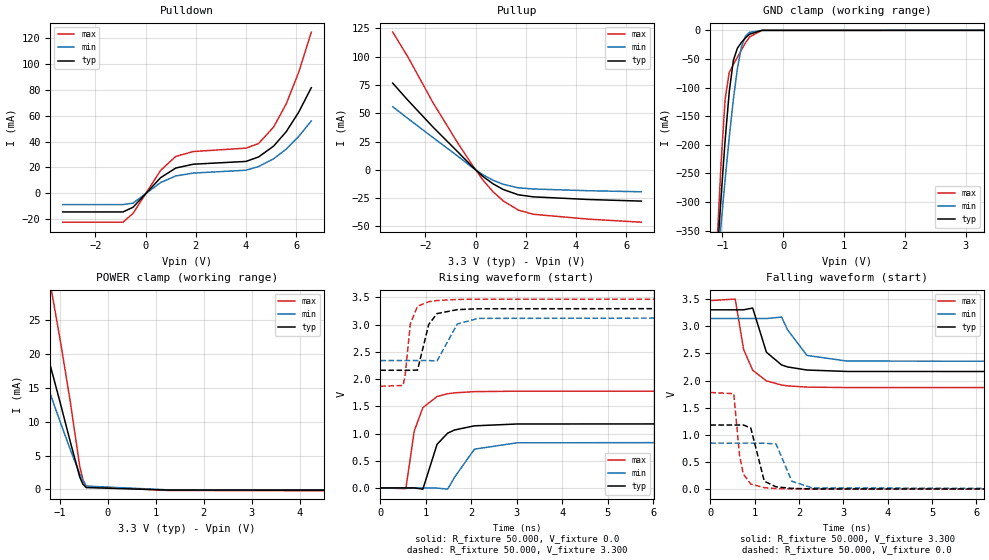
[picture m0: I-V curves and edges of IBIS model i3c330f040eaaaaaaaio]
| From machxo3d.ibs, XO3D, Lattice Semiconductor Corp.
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|   Model i3c330f040eaaaaaaaio
[Model] i3c330f040eaaaaaaaio
Model_type I/O
Polarity   Non-Inverting
Enable   Active-Low
Vinl =  0.800V
Vinh =  2.000V
Vmeas =  1.650V
Cref =  0.0F
Rref =  1.000M
Vref =  0.0V
C_comp   4.200pF   3.800pF   7.500pF
[Temperature Range]   25.000   0.105k   -40.000
[Voltage Range]   3.300V   3.140V   3.470V
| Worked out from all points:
|   slope of the pulldown table from 0 to 0.495 V, typ, clamps not added: 48.6 ohm
|   slope of the pullup table from 0 to 0.495 V, typ, clamps not added: 53.4 ohm
|   GND clamp passes 1 mA (typ) near -0.43 V on its own axis
|   POWER clamp passes 1 mA (typ) near -0.53 V on its own axis
|   rising waveform, R_fixture 50.000, V_fixture 0.0: 20-80 % time 343ps typ, 380ps min, 269ps max; typ from 0.003 V to 1.18 V
|   rising waveform, R_fixture 50.000, V_fixture 3.300: 20-80 % time 198ps typ, 272ps min, 135ps max; typ from 2.16 V to 3.3 V
|   falling waveform, R_fixture 50.000, V_fixture 3.300: 20-80 % time 344ps typ, 364ps min, 324ps max; typ from 3.3 V to 2.16 V
|   falling waveform, R_fixture 50.000, V_fixture 0.0: 20-80 % time 183ps typ, 246ps min, 137ps max; typ from 1.18 V to 0.003 V
[Pulldown]
|Voltage   I(typ)   I(min)   I(max)
-3.3V     -14.66mA   -8.951mA   -22.6mA
-900mV    -14.66mA   -8.951mA   -22.6mA
-500mV    -11.02mA   -7.807mA   -15.8mA
600mV     11.95mA    8.157mA    17.61mA
1.2V      19.4mA     13.27mA    28.41mA
1.9V      22.39mA    15.51mA    32.23mA
4V        24.55mA    17.73mA    34.86mA
4.5V      28.02mA    20.58mA    38.42mA
5.1V      36.46mA    26.61mA    51.28mA
5.6V      47.61mA    34.11mA    69.18mA
6.1V      62.81mA    44mA       93.83mA
6.6V      81.81mA    55.98mA    124.9mA
[Pullup]
|Voltage   I(typ)   I(min)   I(max)
-3.3V     76.62mA    55.76mA    121.7mA
-2.7V     61.61mA    45.47mA    99.98mA
-1.7V     37.92mA    28.61mA    59.52mA
-700mV    15.71mA    11.98mA    23.38mA
-100mV    2.145mA    1.619mA    3.301mA
300mV     -5.911mA   -4.416mA   -9.19mA
700mV     -12.39mA   -9.179mA   -19.41mA
1.1V      -17.33mA   -12.72mA   -27.42mA
1.7V      -22.01mA   -15.86mA   -35.48mA
2.3V      -23.82mA   -16.89mA   -39.22mA
4.5V      -26.17mA   -18.42mA   -43.53mA
6.6V      -27.59mA   -19.35mA   -46.21mA
[GND_clamp]
|Voltage   I(typ)   I(min)   I(max)
-3.3V     -4.506A    -3.482A    -6.262A
-1.089V   -398.3mA   -420.5mA   -374.5mA
-1.022V   -290.6mA   -338.5mA   -230.4mA
-955mV    -191.2mA   -260.1mA   -119.8mA
-888mV    -107.4mA   -186.9mA   -73.47mA
-821mV    -52.87mA   -121.3mA   -59.62mA
-754mV    -31.28mA   -66.86mA   -47.24mA
-687mV    -21.04mA   -28.74mA   -34.02mA
-620mV    -13.09mA   -10.15mA   -21.79mA
-553mV    -6.755mA   -3.505mA   -11.52mA
-352mV    -90.18uA   -45.39uA   -119.9uA
3.3V      0A         0A         0A
[POWER_clamp]
|Voltage   I(typ)   I(min)   I(max)
-3.3V     62.1mA     51.02mA    92.7mA
-1.926V   36.35mA    28.59mA    56.55mA
-1.591V   28.28mA    21.98mA    45.01mA
-1.189V   18.03mA    13.9mA     29.96mA
-1.122V   16.26mA    12.55mA    27.31mA
-988mV    12.68mA    9.882mA    21.88mA
-787mV    7.154mA    5.963mA    13.15mA
-586mV    1.819mA    2.29mA     3.395mA
-519mV    748.7uA    1.242mA    1.434mA
-452mV    255.4uA    468.1uA    442.9uA
1.223V    -104.1uA   -69.89uA   -164.8uA
6.6V      -145.9uA   -91.75uA   -251.2uA
[Ramp]
| variable   typ   min   max
dV/dt_r   0.707/0.346n   0.508/0.376n   1.065/0.269n
dV/dt_f   0.682/0.343n   0.480/0.362n   0.960/0.323n
R_load = 50.000
[Rising Waveform]
R_fixture= 50.000
V_fixture= 0.0
V_fixture_min= 0.0
V_fixture_max= 0.0
|time   V(typ)   V(min)   V(max)
0s        3.283mV    2.496mV    4.478mV
562ps     3.331mV    2.524mV    -9.755mV
747ps     3.487mV    2.493mV    1.05V
936ps     -19.44mV   2.569mV    1.477V
1.248ns   804.3mV    200.3uV    1.681V
1.481ns   1.009V     -18.34mV   1.732V
1.636ns   1.068V     202.8mV    1.749V
2.069ns   1.143V     714.8mV    1.771V
3.005ns   1.177V     831.7mV    1.779V
20ns      1.182V     848.7mV    1.78V
[Rising Waveform]
R_fixture= 50.000
V_fixture= 3.300
V_fixture_min= 3.140
V_fixture_max= 3.470
|time   V(typ)   V(min)   V(max)
0s        2.163V     2.341V     1.87V
502ps     2.163V     2.341V     1.884V
548ps     2.163V     2.341V     2.084V
661ps     2.163V     2.341V     3.015V
819ps     2.167V     2.341V     3.339V
1.064ns   3.003V     2.342V     3.421V
1.246ns   3.203V     2.332V     3.443V
1.693ns   3.276V     3.013V     3.463V
2.148ns   3.292V     3.115V     3.468V
20ns      3.3V       3.14V      3.47V
[Falling Waveform]
R_fixture= 50.000
V_fixture= 3.300
V_fixture_min= 3.140
V_fixture_max= 3.470
|time   V(typ)   V(min)   V(max)
0s        3.3V       3.14V      3.47V
563ps     3.3V       3.14V      3.498V
751ps     3.3V       3.14V      2.571V
956ps     3.333V     3.14V      2.189V
1.265ns   2.521V     3.14V      1.994V
1.608ns   2.286V     3.167V     1.917V
1.741ns   2.25V      2.934V     1.902V
2.178ns   2.193V     2.462V     1.879V
3.082ns   2.167V     2.358V     1.871V
20ns      2.163V     2.341V     1.87V
[Falling Waveform]
R_fixture= 50.000
V_fixture= 0.0
V_fixture_min= 0.0
V_fixture_max= 0.0
|time   V(typ)   V(min)   V(max)
0s        1.182V     848.7mV    1.78V
529ps     1.182V     848.6mV    1.759V
659ps     1.182V     848.7mV    629mV
745ps     1.182V     848.7mV    281mV
913ps     1.128V     848.8mV    96.79mV
1.218ns   148.3mV    848.3mV    29.53mV
1.483ns   45.36mV    831.6mV    13.69mV
1.839ns   16.89mV    147.2mV    7.059mV
2.304ns   6.748mV    24.42mV    5.06mV
20ns      3.283mV    2.496mV    4.478mV
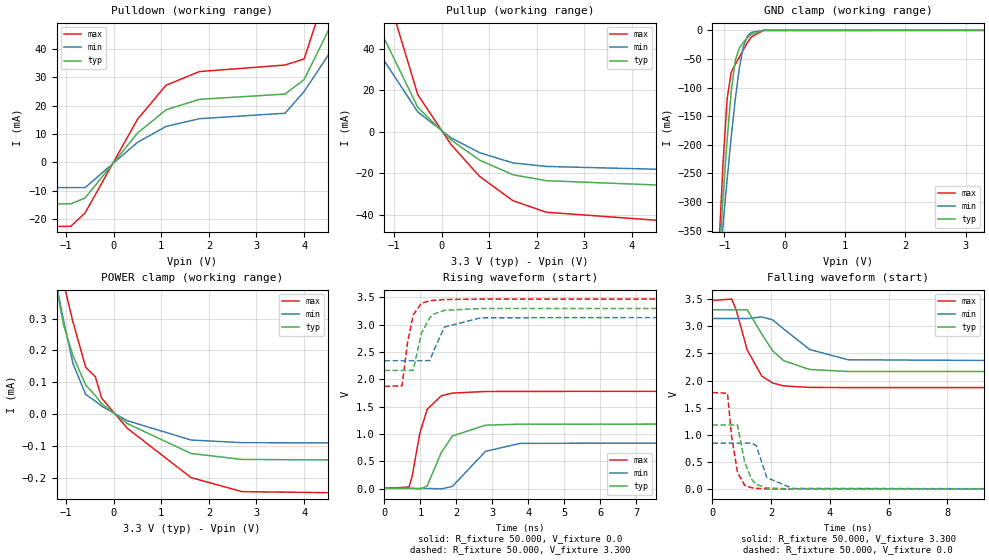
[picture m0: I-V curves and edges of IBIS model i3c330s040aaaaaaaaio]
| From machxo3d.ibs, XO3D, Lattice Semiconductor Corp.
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|   Model i3c330s040aaaaaaaaio
[Model] i3c330s040aaaaaaaaio
Model_type I/O
Polarity   Non-Inverting
Enable   Active-Low
Vinl =  0.800V
Vinh =  2.000V
Vmeas =  1.650V
Cref =  0.0F
Rref =  1.000M
Vref =  0.0V
C_comp   4.200pF   3.800pF   7.500pF
[Temperature Range]   25.000   0.105k   -40.000
[Voltage Range]   3.300V   3.140V   3.470V
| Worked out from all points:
|   slope of the pulldown table from 0 to 0.495 V, typ, clamps not added: 48.6 ohm
|   slope of the pullup table from 0 to 0.495 V, typ, clamps not added: 53.4 ohm
|   GND clamp passes 1 mA (typ) near -0.43 V on its own axis
|   POWER clamp passes 1 mA (typ) near -1.85 V on its own axis
|   rising waveform, R_fixture 50.000, V_fixture 0.0: 20-80 % time 530ps typ, 714ps min, 362ps max; typ from 0.003 V to 1.18 V
|   rising waveform, R_fixture 50.000, V_fixture 3.300: 20-80 % time 314ps typ, 356ps min, 236ps max; typ from 2.16 V to 3.3 V
|   falling waveform, R_fixture 50.000, V_fixture 3.300: 20-80 % time 887ps typ, 1.24ns min, 634ps max; typ from 3.3 V to 2.16 V
|   falling waveform, R_fixture 50.000, V_fixture 0.0: 20-80 % time 324ps typ, 380ps min, 259ps max; typ from 1.18 V to 0.003 V
[Pulldown]
|Voltage   I(typ)   I(min)   I(max)
-3.3V     -14.66mA   -8.951mA   -22.6mA
-900mV    -14.66mA   -8.951mA   -22.6mA
-600mV    -12.62mA   -8.951mA   -17.88mA
500mV     10.27mA    7.01mA     15.14mA
1.1V      18.49mA    12.63mA    27.15mA
1.8V      22.18mA    15.35mA    31.97mA
3.6V      24.04mA    17.29mA    34.28mA
4V        29.15mA    24.94mA    36.43mA
4.6V      49.5mA     40.11mA    67.13mA
5V        64.78mA    51.73mA    90.47mA
5.5V      86.24mA    67.68mA    123.5mA
6.6V      140mA      105.9mA    207.2mA
[Pullup]
|Voltage   I(typ)   I(min)   I(max)
-3.3V     100.7mA    71.26mA    161mA
-2.7V     100.7mA    71.26mA    161mA
-2.5V     97.56mA    71.26mA    154.8mA
-2.2V     87.92mA    66.12mA    139mA
-1.7V     67.5mA     51.18mA    106.8mA
-1.2V     44.66mA    33.97mA    71.11mA
-500mV    11.69mA    9.496mA    17.83mA
200mV     -4.043mA   -3.026mA   -6.275mA
800mV     -13.76mA   -10.18mA   -21.62mA
1.5V      -20.8mA    -15.09mA   -33.3mA
2.2V      -23.66mA   -16.79mA   -38.85mA
6.6V      -27.59mA   -19.35mA   -46.21mA
[GND_clamp]
|Voltage   I(typ)   I(min)   I(max)
-3.3V     -4.506A    -3.482A    -6.262A
-1.089V   -398.3mA   -420.5mA   -374.5mA
-1.022V   -290.6mA   -338.5mA   -230.4mA
-955mV    -191.2mA   -260.1mA   -119.8mA
-888mV    -107.4mA   -186.9mA   -73.47mA
-821mV    -52.87mA   -121.3mA   -59.62mA
-754mV    -31.28mA   -66.86mA   -47.24mA
-687mV    -21.04mA   -28.74mA   -34.02mA
-620mV    -13.09mA   -10.15mA   -21.79mA
-553mV    -6.755mA   -3.505mA   -11.52mA
-352mV    -90.18uA   -45.39uA   -119.9uA
3.3V      0A         0A         0A
[POWER_clamp]
|Voltage   I(typ)   I(min)   I(max)
-3.3V     3.967mA    2.512mA    11.53mA
-1.323V   507.3uA    506.4uA    605.6uA
-1.189V   387.7uA    399.8uA    501.1uA
-1.055V   282.8uA    296.7uA    413.8uA
-854mV    182.6uA    158.2uA    289.7uA
-586mV    90.73uA    61.33uA    146.6uA
-385mV    58.36uA    40.66uA    117.5uA
-251mV    32.53uA    24.74uA    49.87uA
285mV     -29.95uA   -20.85uA   -44.72uA
1.625V    -124uA     -81.72uA   -199.9uA
2.697V    -142.9uA   -90.03uA   -244.1uA
6.6V      -145.9uA   -91.75uA   -251.2uA
[Ramp]
| variable   typ   min   max
dV/dt_r   0.707/0.532n   0.508/0.720n   1.065/0.363n
dV/dt_f   0.682/0.894n   0.480/1.224n   0.960/0.631n
R_load = 50.000
[Rising Waveform]
R_fixture= 50.000
V_fixture= 0.0
V_fixture_min= 0.0
V_fixture_max= 0.0
|time   V(typ)   V(min)   V(max)
0s        3.283mV    2.496mV    4.478mV
684ps     3.837mV    2.493mV    27.02mV
767ps     2.309mV    2.493mV    216.7mV
984ps     -11.68mV   2.57mV     1.017V
1.188ns   48.65mV    2.528mV    1.451V
1.582ns   662.8mV    -7.164mV   1.7V
1.887ns   961.9mV    38.18mV    1.748V
2.806ns   1.16V      680.4mV    1.777V
3.769ns   1.179V     827.2mV    1.779V
20ns      1.182V     848.7mV    1.78V
[Rising Waveform]
R_fixture= 50.000
V_fixture= 3.300
V_fixture_min= 3.140
V_fixture_max= 3.470
|time   V(typ)   V(min)   V(max)
0s        2.163V     2.341V     1.87V
489ps     2.163V     2.341V     1.883V
636ps     2.163V     2.341V     2.65V
799ps     2.165V     2.341V     3.179V
1.028ns   2.842V     2.341V     3.394V
1.26ns    3.129V     2.343V     3.438V
1.37ns    3.195V     2.526V     3.448V
1.666ns   3.263V     2.957V     3.461V
2.68ns    3.297V     3.127V     3.47V
20ns      3.3V       3.14V      3.47V
[Falling Waveform]
R_fixture= 50.000
V_fixture= 3.300
V_fixture_min= 3.140
V_fixture_max= 3.470
|time   V(typ)   V(min)   V(max)
0s        3.3V       3.14V      3.47V
659ps     3.299V     3.14V      3.497V
811ps     3.299V     3.14V      3.296V
1.186ns   3.298V     3.139V     2.562V
1.68ns    2.856V     3.168V     2.082V
2.055ns   2.543V     3.114V     1.953V
2.433ns   2.363V     2.944V     1.901V
3.311ns   2.202V     2.57V      1.873V
4.617ns   2.166V     2.381V     1.87V
20ns      2.163V     2.341V     1.87V
[Falling Waveform]
R_fixture= 50.000
V_fixture= 0.0
V_fixture_min= 0.0
V_fixture_max= 0.0
|time   V(typ)   V(min)   V(max)
0s        1.182V     848.7mV    1.78V
516ps     1.182V     848.6mV    1.764V
647ps     1.182V     848.7mV    1.004V
855ps     1.182V     848.7mV    310.5mV
1.1ns     495.3mV    848.5mV    71.63mV
1.336ns   184.8mV    849.4mV    28.36mV
1.495ns   90.88mV    800.5mV    17.52mV
1.854ns   24.7mV     215.7mV    8.054mV
2.722ns   5.272mV    16.8mV     4.769mV
20ns      3.283mV    2.496mV    4.478mV
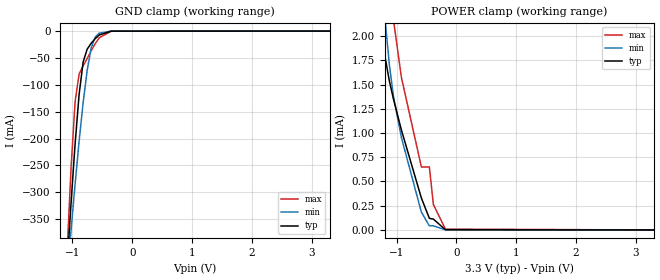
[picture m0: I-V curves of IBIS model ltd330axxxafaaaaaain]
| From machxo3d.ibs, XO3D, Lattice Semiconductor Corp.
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|   Model ltd330axxxafaaaaaain
[Model] ltd330axxxafaaaaaain
Model_type Input
Polarity   Non-Inverting
Enable   Active-High
Vinl =  0.800V
Vinh =  2.000V
C_comp   4.200pF   3.800pF   7.500pF
[Temperature Range]   25.000   0.105k   -40.000
[Voltage Range]   3.300V   3.140V   3.470V
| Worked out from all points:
|   GND clamp passes 1 mA (typ) near -0.43 V on its own axis
|   POWER clamp passes 1 mA (typ) near -0.91 V on its own axis
[GND_clamp]
|Voltage   I(typ)   I(min)   I(max)
-3.3V     -4.913A    -3.768A    -6.865A
-1.089V   -436.6mA   -458.9mA   -411.5mA
-1.022V   -318.8mA   -370mA     -253.2mA
-955mV    -210mA     -284.8mA   -131.4mA
-888mV    -117.9mA   -205.1mA   -80.02mA
-821mV    -57.76mA   -133.4mA   -64.74mA
-754mV    -33.88mA   -73.63mA   -51.23mA
-687mV    -22.76mA   -31.63mA   -36.92mA
-620mV    -14.21mA   -11.16mA   -23.73mA
-553mV    -7.411mA   -3.893mA   -12.67mA
-352mV    -131.3uA   -58.9uA    -219uA
3.3V      0A         0A         0A
[POWER_clamp]
|Voltage   I(typ)   I(min)   I(max)
-3.3V     32.67mA    26.87mA    52.85mA
-1.323V   2.804mA    3.246mA    8.665mA
-1.256V   2.134mA    2.67mA     6.124mA
-1.189V   1.77mA     2.147mA    4.184mA
-1.122V   1.54mA     1.71mA     2.893mA
-1.055V   1.357mA    1.39mA     2.18mA
-921mV    1.034mA    956.5uA    1.578mA
-586mV    330uA      184.5uA    649.8uA
-452mV    119.7uA    42.63uA    649.8uA
-385mV    112.2uA    42.63uA    262.6uA
-184mV    2.18uA     1.689uA    8.903uA
3.3V      0A         0A         0A
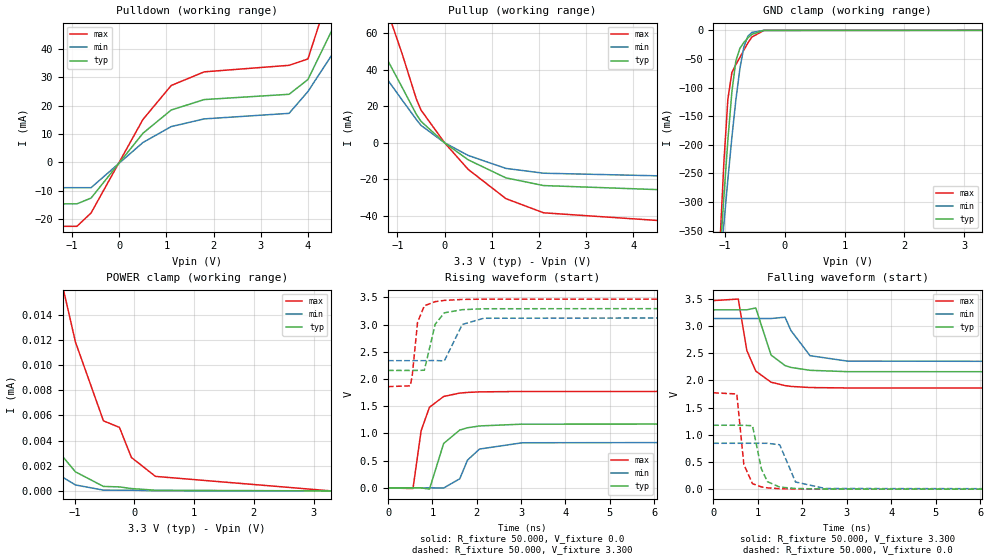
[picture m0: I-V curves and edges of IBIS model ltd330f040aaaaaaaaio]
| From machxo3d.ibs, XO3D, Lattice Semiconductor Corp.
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|   Model ltd330f040aaaaaaaaio
[Model] ltd330f040aaaaaaaaio
Model_type I/O
Polarity   Non-Inverting
Enable   Active-Low
Vinl =  0.800V
Vinh =  2.000V
Vmeas =  1.650V
Cref =  0.0F
Rref =  1.000M
Vref =  0.0V
C_comp   4.200pF   3.800pF   7.500pF
[Temperature Range]   25.000   0.105k   -40.000
[Voltage Range]   3.300V   3.140V   3.470V
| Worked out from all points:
|   slope of the pulldown table from 0 to 0.495 V, typ, clamps not added: 48.6 ohm
|   slope of the pullup table from 0 to 0.495 V, typ, clamps not added: 53.4 ohm
|   GND clamp passes 1 mA (typ) near -0.43 V on its own axis
|   rising waveform, R_fixture 50.000, V_fixture 0.0: 20-80 % time 331ps typ, 367ps min, 261ps max; typ from 0 V to 1.18 V
|   rising waveform, R_fixture 50.000, V_fixture 3.300: 20-80 % time 195ps typ, 269ps min, 132ps max; typ from 2.16 V to 3.3 V
|   falling waveform, R_fixture 50.000, V_fixture 3.300: 20-80 % time 333ps typ, 365ps min, 313ps max; typ from 3.3 V to 2.16 V
|   falling waveform, R_fixture 50.000, V_fixture 0.0: 20-80 % time 178ps typ, 241ps min, 133ps max; typ from 1.18 V to 0 V
[Pulldown]
|Voltage   I(typ)   I(min)   I(max)
-3.3V     -14.66mA   -8.951mA   -22.6mA
-900mV    -14.66mA   -8.951mA   -22.6mA
-600mV    -12.62mA   -8.951mA   -17.88mA
500mV     10.27mA    7.01mA     15.14mA
1.1V      18.49mA    12.63mA    27.15mA
1.8V      22.18mA    15.35mA    31.97mA
3.6V      24.04mA    17.31mA    34.28mA
4V        29.25mA    25.01mA    36.52mA
4.6V      49.79mA    40.29mA    67.43mA
5V        65.22mA    51.84mA    90.99mA
5.5V      86.65mA    67.52mA    124.4mA
6.6V      140.5mA    103.6mA    211.2mA
[Pullup]
|Voltage   I(typ)   I(min)   I(max)
-3.3V     135.2mA    102.3mA    210.5mA
-2.8V     116.5mA    88.68mA    183.8mA
-2.4V     99.85mA    76.1mA     157.6mA
-1.3V     49.65mA    37.77mA    78.8mA
-900mV    30.35mA    23.38mA    48.71mA
-600mV    15.57mA    12.77mA    24.03mA
-500mV    11.73mA    9.516mA    17.91mA
0V        90fA       652fA      300fA
500mV     -9.346mA   -6.955mA   -14.59mA
1.3V      -19.24mA   -14.05mA   -30.62mA
2.1V      -23.46mA   -16.69mA   -38.39mA
6.6V      -27.59mA   -19.35mA   -46.21mA
[GND_clamp]
|Voltage   I(typ)   I(min)   I(max)
-3.3V     -4.507A    -3.482A    -6.263A
-1.089V   -398.4mA   -420.6mA   -374.7mA
-1.022V   -290.7mA   -338.6mA   -230.6mA
-955mV    -191.4mA   -260.2mA   -120.1mA
-888mV    -107.5mA   -187mA     -73.69mA
-821mV    -53mA      -121.4mA   -59.83mA
-754mV    -31.41mA   -66.95mA   -47.44mA
-687mV    -21.17mA   -28.83mA   -34.23mA
-620mV    -13.21mA   -10.24mA   -21.98mA
-553mV    -6.877mA   -3.592mA   -11.71mA
-352mV    -122.8uA   -54.62uA   -209.3uA
3.3V      0A         0A         0A
[POWER_clamp]
|Voltage   I(typ)   I(min)   I(max)
-3.3V     530uA      347.3uA    956.2uA
-2.663V   63.57uA    15.44uA    254.2uA
-2.529V   27.42uA    10.98uA    148.7uA
-2.328V   15.78uA    8.532uA    64.82uA
-1.725V   7.398uA    3.713uA    31uA
-1.189V   2.659uA    1.053uA    15.99uA
-988mV    1.516uA    474.5nA    11.83uA
-519mV    357.5nA    63.29nA    5.567uA
-251mV    319nA      55.54nA    5.047uA
-50mV     187.6nA    55.54nA    2.655uA
352mV     56.19nA    7.349nA    1.154uA
3.3V      0A         0A         0A
[Ramp]
| variable   typ   min   max
dV/dt_r   0.705/0.333n   0.507/0.366n   1.064/0.262n
dV/dt_f   0.685/0.332n   0.481/0.352n   0.965/0.312n
R_load = 50.000
[Rising Waveform]
R_fixture= 50.000
V_fixture= 0.0
V_fixture_min= 0.0
V_fixture_max= 0.0
|time   V(typ)   V(min)   V(max)
0s        26.18nV    63.38nV    354.7nV
563ps     44.2uV     -1.73uV    -13.39mV
747ps     186uV      -1.73uV    1.052V
935ps     -24.01mV   94.32uV    1.482V
1.255ns   816.5mV    -2.366mV   1.68V
1.618ns   1.063V     167mV      1.742V
1.791ns   1.104V     508mV      1.754V
2.062ns   1.138V     713.1mV    1.764V
3.03ns    1.171V     829mV      1.772V
20ns      1.176V     844.4mV    1.773V
[Rising Waveform]
R_fixture= 50.000
V_fixture= 3.300
V_fixture_min= 3.140
V_fixture_max= 3.470
|time   V(typ)   V(min)   V(max)
0s        2.158V     2.338V     1.861V
502ps     2.158V     2.338V     1.875V
547ps     2.158V     2.338V     2.068V
666ps     2.159V     2.338V     3.044V
819ps     2.162V     2.338V     3.346V
1.065ns   3.01V      2.34V      3.423V
1.271ns   3.217V     2.334V     3.446V
1.674ns   3.275V     3.003V     3.463V
2.158ns   3.292V     3.117V     3.468V
20ns      3.3V       3.14V      3.47V
[Falling Waveform]
R_fixture= 50.000
V_fixture= 3.300
V_fixture_min= 3.140
V_fixture_max= 3.470
|time   V(typ)   V(min)   V(max)
0s        3.3V       3.14V      3.47V
563ps     3.3V       3.14V      3.498V
753ps     3.3V       3.14V      2.554V
955ps     3.334V     3.14V      2.172V
1.298ns   2.468V     3.14V      1.968V
1.613ns   2.274V     3.164V     1.906V
1.744ns   2.24V      2.92V      1.891V
2.174ns   2.187V     2.456V     1.87V
3.018ns   2.162V     2.356V     1.862V
20ns      2.158V     2.338V     1.861V
[Falling Waveform]
R_fixture= 50.000
V_fixture= 0.0
V_fixture_min= 0.0
V_fixture_max= 0.0
|time   V(typ)   V(min)   V(max)
0s        1.176V     844.4mV    1.773V
529ps     1.176V     844.4mV    1.752V
688ps     1.175V     844.4mV    450.3mV
882ps     1.167V     844.5mV    101.2mV
1.08ns    376.6mV    844.3mV    41.8mV
1.217ns   138.1mV    844mV      23.92mV
1.493ns   37.92mV    816.8mV    8.539mV
1.848ns   12.65mV    132.3mV    2.57mV
2.519ns   1.936mV    11.56mV    326.6uV
20ns      -182.5nV   107.5nV    307.8nV
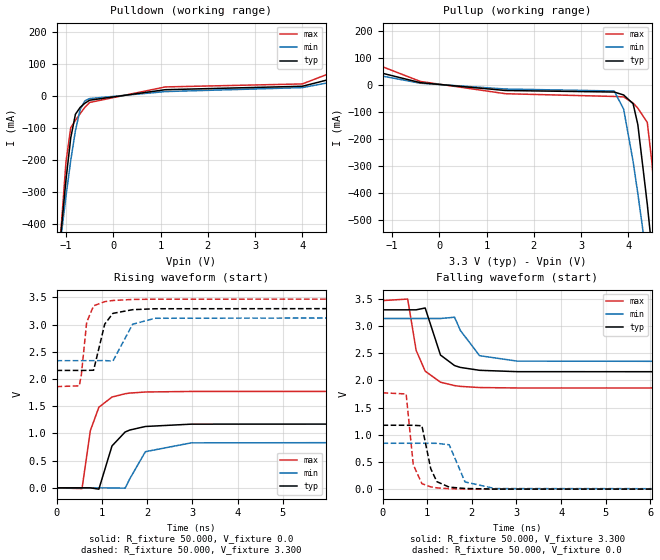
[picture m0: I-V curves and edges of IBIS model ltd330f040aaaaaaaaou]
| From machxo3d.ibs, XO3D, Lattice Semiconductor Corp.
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|   Model ltd330f040aaaaaaaaou
[Model] ltd330f040aaaaaaaaou
Model_type Output
Polarity   Non-Inverting
Enable   Active-High
Vmeas =  1.650V
Cref =  0.0F
Rref =  1.000M
Vref =  0.0V
C_comp   4.200pF   3.800pF   7.500pF
[Temperature Range]   25.000   0.105k   -40.000
[Voltage Range]   3.300V   3.140V   3.470V
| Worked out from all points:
|   slope of the pulldown table from 0 to 0.495 V, typ, clamps not added: 48.6 ohm
|   slope of the pullup table from 0 to 0.495 V, typ, clamps not added: 53.4 ohm
|   rising waveform, R_fixture 50.000, V_fixture 0.0: 20-80 % time 335ps typ, 367ps min, 261ps max; typ from 0 V to 1.18 V
|   rising waveform, R_fixture 50.000, V_fixture 3.300: 20-80 % time 195ps typ, 268ps min, 132ps max; typ from 2.16 V to 3.3 V
|   falling waveform, R_fixture 50.000, V_fixture 3.300: 20-80 % time 333ps typ, 365ps min, 313ps max; typ from 3.3 V to 2.16 V
|   falling waveform, R_fixture 50.000, V_fixture 0.0: 20-80 % time 178ps typ, 241ps min, 133ps max; typ from 1.18 V to 0 V
[Pulldown]
|Voltage   I(typ)   I(min)   I(max)
-3.3V     -4.507A    -3.482A    -6.263A
-1.1V     -420mA     -435.9mA   -408.3mA
-1V       -263.3mA   -314.6mA   -207.1mA
-900mV    -132.7mA   -203.2mA   -100.5mA
-800mV    -58.26mA   -109.1mA   -77.28mA
-700mV    -36.8mA    -43.36mA   -56.32mA
-600mV    -23.75mA   -16.45mA   -36.55mA
-500mV    -14.34mA   -9.257mA   -21.46mA
1.1V      18.49mA    12.63mA    27.15mA
4V        29.25mA    25.01mA    36.52mA
5.3V      77.81mA    61.11mA    110.5mA
6.6V      141mA      104.1mA    211.9mA
[Pullup]
|Voltage   I(typ)   I(min)   I(max)
-3.3V     135.7mA    102.7mA    211.4mA
-400mV    8.958mA    6.933mA    13.6mA
1.4V      -20.07mA   -14.6mA    -32.02mA
3.7V      -25.8mA    -21.94mA   -42.22mA
3.9V      -36.71mA   -89.31mA   -43.89mA
4.1V      -69.38mA   -284.1mA   -66.57mA
4.2V      -146.7mA   -403mA     -85.72mA
4.4V      -442.8mA   -658.2mA   -138.5mA
4.5V      -613.1mA   -790.6mA   -290.2mA
4.6V      -789.1mA   -924.9mA   -514mA
4.7V      -968.5mA   -1.061A    -759.2mA
6.6V      -4.534A    -3.729A    -5.846A
[Ramp]
| variable   typ   min   max
dV/dt_r   0.705/0.333n   0.507/0.366n   1.064/0.262n
dV/dt_f   0.685/0.332n   0.481/0.352n   0.965/0.312n
R_load = 50.000
[Rising Waveform]
R_fixture= 50.000
V_fixture= 0.0
V_fixture_min= 0.0
V_fixture_max= 0.0
|time   V(typ)   V(min)   V(max)
0s        26.18nV    63.38nV    354.7nV
563ps     44.19uV    -1.694uV   -13.39mV
747ps     186uV      -1.694uV   1.052V
935ps     -24.01mV   94.32uV    1.482V
1.225ns   770.7mV    -803.2uV   1.669V
1.515ns   1.026V     -5.898mV   1.73V
1.618ns   1.063V     167mV      1.742V
1.963ns   1.128V     665mV      1.762V
2.976ns   1.171V     827.2mV    1.772V
20ns      1.176V     844.4mV    1.773V
[Rising Waveform]
R_fixture= 50.000
V_fixture= 3.300
V_fixture_min= 3.140
V_fixture_max= 3.470
|time   V(typ)   V(min)   V(max)
0s        2.158V     2.338V     1.861V
502ps     2.158V     2.338V     1.875V
547ps     2.158V     2.338V     2.068V
666ps     2.159V     2.338V     3.044V
819ps     2.162V     2.338V     3.346V
1.065ns   3.01V      2.34V      3.423V
1.245ns   3.207V     2.329V     3.444V
1.68ns    3.275V     3.007V     3.463V
2.176ns   3.292V     3.117V     3.468V
20ns      3.3V       3.14V      3.47V
[Falling Waveform]
R_fixture= 50.000
V_fixture= 3.300
V_fixture_min= 3.140
V_fixture_max= 3.470
|time   V(typ)   V(min)   V(max)
0s        3.3V       3.14V      3.47V
563ps     3.3V       3.14V      3.498V
753ps     3.3V       3.14V      2.554V
955ps     3.334V     3.14V      2.172V
1.298ns   2.468V     3.14V      1.968V
1.613ns   2.274V     3.164V     1.906V
1.744ns   2.24V      2.92V      1.891V
2.174ns   2.187V     2.456V     1.87V
3.018ns   2.162V     2.356V     1.862V
20ns      2.158V     2.338V     1.861V
[Falling Waveform]
R_fixture= 50.000
V_fixture= 0.0
V_fixture_min= 0.0
V_fixture_max= 0.0
|time   V(typ)   V(min)   V(max)
0s        1.176V     844.4mV    1.773V
529ps     1.176V     844.4mV    1.752V
688ps     1.175V     844.4mV    450.3mV
882ps     1.167V     844.5mV    101.2mV
1.08ns    376.6mV    844.3mV    41.8mV
1.217ns   138.1mV    844mV      23.92mV
1.493ns   37.92mV    816.8mV    8.539mV
1.848ns   12.65mV    132.3mV    2.57mV
2.519ns   1.936mV    11.56mV    326.6uV
20ns      -182.5nV   107.5nV    307.8nV
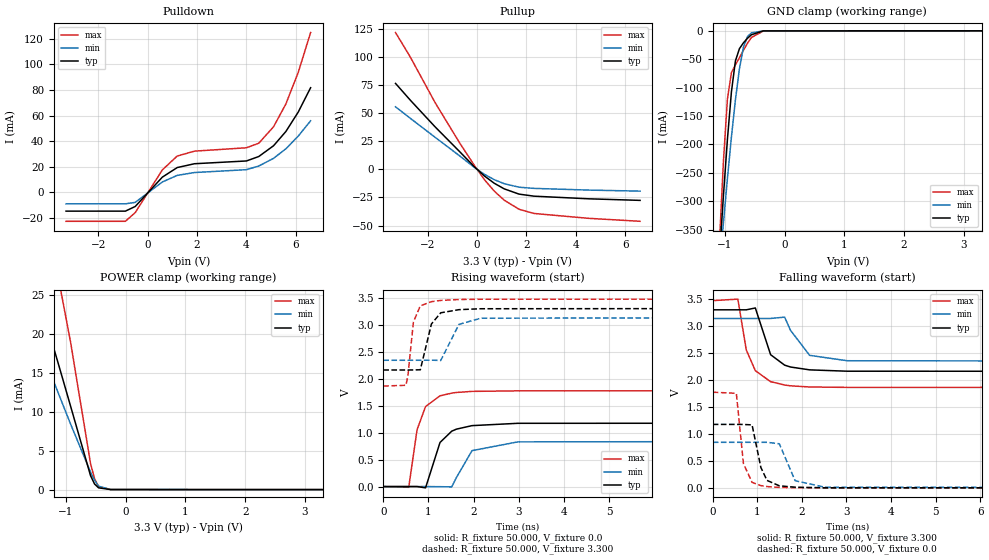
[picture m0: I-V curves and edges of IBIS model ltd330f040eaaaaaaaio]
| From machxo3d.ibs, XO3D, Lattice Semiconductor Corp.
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|   Model ltd330f040eaaaaaaaio
[Model] ltd330f040eaaaaaaaio
Model_type I/O
Polarity   Non-Inverting
Enable   Active-Low
Vinl =  0.800V
Vinh =  2.000V
Vmeas =  1.650V
Cref =  0.0F
Rref =  1.000M
Vref =  0.0V
C_comp   4.200pF   3.800pF   7.500pF
[Temperature Range]   25.000   0.105k   -40.000
[Voltage Range]   3.300V   3.140V   3.470V
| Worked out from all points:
|   slope of the pulldown table from 0 to 0.495 V, typ, clamps not added: 48.6 ohm
|   slope of the pullup table from 0 to 0.495 V, typ, clamps not added: 53.4 ohm
|   GND clamp passes 1 mA (typ) near -0.43 V on its own axis
|   POWER clamp passes 1 mA (typ) near -0.54 V on its own axis
|   rising waveform, R_fixture 50.000, V_fixture 0.0: 20-80 % time 337ps typ, 367ps min, 261ps max; typ from 0 V to 1.18 V
|   rising waveform, R_fixture 50.000, V_fixture 3.300: 20-80 % time 195ps typ, 269ps min, 132ps max; typ from 2.16 V to 3.3 V
|   falling waveform, R_fixture 50.000, V_fixture 3.300: 20-80 % time 333ps typ, 365ps min, 313ps max; typ from 3.3 V to 2.16 V
|   falling waveform, R_fixture 50.000, V_fixture 0.0: 20-80 % time 178ps typ, 241ps min, 133ps max; typ from 1.18 V to 0 V
[Pulldown]
|Voltage   I(typ)   I(min)   I(max)
-3.3V     -14.66mA   -8.951mA   -22.6mA
-900mV    -14.66mA   -8.951mA   -22.6mA
-500mV    -11.02mA   -7.807mA   -15.8mA
600mV     11.95mA    8.157mA    17.61mA
1.2V      19.4mA     13.27mA    28.41mA
1.9V      22.39mA    15.52mA    32.23mA
4V        24.55mA    17.73mA    34.86mA
4.5V      28.02mA    20.58mA    38.42mA
5.1V      36.46mA    26.61mA    51.29mA
5.6V      47.62mA    34.1mA     69.18mA
6.1V      62.81mA    44mA       93.83mA
6.6V      81.81mA    55.97mA    124.9mA
[Pullup]
|Voltage   I(typ)   I(min)   I(max)
-3.3V     76.54mA    55.7mA     121.8mA
-2.7V     61.58mA    45.45mA    99.96mA
-1.7V     37.91mA    28.6mA     59.51mA
-700mV    15.71mA    11.98mA    23.38mA
-100mV    2.145mA    1.619mA    3.301mA
300mV     -5.911mA   -4.416mA   -9.19mA
700mV     -12.39mA   -9.179mA   -19.41mA
1.1V      -17.33mA   -12.72mA   -27.42mA
1.7V      -22.01mA   -15.86mA   -35.48mA
2.3V      -23.83mA   -16.9mA    -39.22mA
4.5V      -26.17mA   -18.42mA   -43.54mA
6.6V      -27.59mA   -19.35mA   -46.21mA
[GND_clamp]
|Voltage   I(typ)   I(min)   I(max)
-3.3V     -4.507A    -3.482A    -6.263A
-1.089V   -398.4mA   -420.6mA   -374.7mA
-1.022V   -290.7mA   -338.6mA   -230.6mA
-955mV    -191.4mA   -260.2mA   -120.1mA
-888mV    -107.5mA   -187mA     -73.69mA
-821mV    -53mA      -121.4mA   -59.83mA
-754mV    -31.41mA   -66.95mA   -47.44mA
-687mV    -21.17mA   -28.83mA   -34.23mA
-620mV    -13.21mA   -10.24mA   -21.98mA
-553mV    -6.877mA   -3.592mA   -11.71mA
-352mV    -122.8uA   -54.62uA   -209.3uA
3.3V      0A         0A         0A
[POWER_clamp]
|Voltage   I(typ)   I(min)   I(max)
-3.3V     59.07mA    46.89mA    89.53mA
-1.993V   37.2mA     28.86mA    58.21mA
-1.926V   35.72mA    27.66mA    56.06mA
-1.591V   27.94mA    21.43mA    44.69mA
-1.189V   17.87mA    13.66mA    29.79mA
-1.122V   16.12mA    12.35mA    27.17mA
-921mV    10.77mA    8.455mA    19.02mA
-586mV    1.798mA    2.256mA    3.367mA
-519mV    726.5uA    1.214mA    1.405mA
-452mV    229.1uA    443uA      409.2uA
-251mV    5.569uA    5.296uA    9.168uA
3.3V      0A         0A         0A
[Ramp]
| variable   typ   min   max
dV/dt_r   0.705/0.333n   0.507/0.366n   1.064/0.262n
dV/dt_f   0.685/0.332n   0.481/0.352n   0.965/0.312n
R_load = 50.000
[Rising Waveform]
R_fixture= 50.000
V_fixture= 0.0
V_fixture_min= 0.0
V_fixture_max= 0.0
|time   V(typ)   V(min)   V(max)
0s        26.18nV    63.38nV    354.7nV
563ps     44.18uV    -1.731uV   -13.39mV
747ps     186uV      -1.731uV   1.052V
935ps     -24.01mV   94.32uV    1.482V
1.255ns   816.5mV    -2.366mV   1.68V
1.515ns   1.026V     -5.898mV   1.73V
1.618ns   1.063V     167mV      1.742V
1.963ns   1.128V     665mV      1.762V
2.976ns   1.171V     827.2mV    1.772V
20ns      1.176V     844.4mV    1.773V
[Rising Waveform]
R_fixture= 50.000
V_fixture= 3.300
V_fixture_min= 3.140
V_fixture_max= 3.470
|time   V(typ)   V(min)   V(max)
0s        2.158V     2.338V     1.861V
502ps     2.158V     2.338V     1.875V
547ps     2.158V     2.338V     2.068V
666ps     2.159V     2.338V     3.044V
819ps     2.162V     2.338V     3.346V
1.065ns   3.01V      2.34V      3.423V
1.271ns   3.217V     2.334V     3.446V
1.674ns   3.275V     3.003V     3.463V
2.158ns   3.292V     3.117V     3.468V
20ns      3.3V       3.14V      3.47V
[Falling Waveform]
R_fixture= 50.000
V_fixture= 3.300
V_fixture_min= 3.140
V_fixture_max= 3.470
|time   V(typ)   V(min)   V(max)
0s        3.3V       3.14V      3.47V
563ps     3.3V       3.14V      3.498V
753ps     3.3V       3.14V      2.554V
955ps     3.334V     3.14V      2.172V
1.298ns   2.468V     3.14V      1.968V
1.613ns   2.274V     3.164V     1.906V
1.744ns   2.24V      2.92V      1.891V
2.174ns   2.187V     2.456V     1.87V
3.018ns   2.162V     2.356V     1.862V
20ns      2.158V     2.338V     1.861V
[Falling Waveform]
R_fixture= 50.000
V_fixture= 0.0
V_fixture_min= 0.0
V_fixture_max= 0.0
|time   V(typ)   V(min)   V(max)
0s        1.176V     844.4mV    1.773V
529ps     1.176V     844.4mV    1.752V
688ps     1.175V     844.4mV    450.3mV
882ps     1.167V     844.5mV    101.2mV
1.08ns    376.6mV    844.3mV    41.8mV
1.217ns   138.1mV    844mV      23.92mV
1.493ns   37.92mV    816.8mV    8.539mV
1.848ns   12.65mV    132.3mV    2.57mV
2.519ns   1.936mV    11.56mV    326.6uV
20ns      -182.5nV   107.5nV    307.8nV
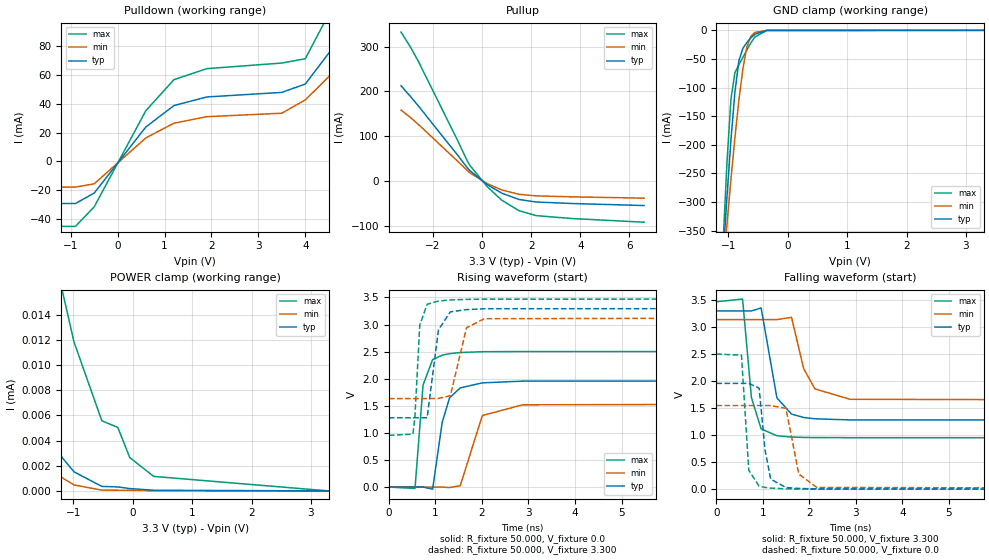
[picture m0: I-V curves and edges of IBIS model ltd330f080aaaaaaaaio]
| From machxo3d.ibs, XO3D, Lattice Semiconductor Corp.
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|   Model ltd330f080aaaaaaaaio
[Model] ltd330f080aaaaaaaaio
Model_type I/O
Polarity   Non-Inverting
Enable   Active-Low
Vinl =  0.800V
Vinh =  2.000V
Vmeas =  1.650V
Cref =  0.0F
Rref =  1.000M
Vref =  0.0V
C_comp   4.200pF   3.800pF   7.500pF
[Temperature Range]   25.000   0.105k   -40.000
[Voltage Range]   3.300V   3.140V   3.470V
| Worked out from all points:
|   slope of the pulldown table from 0 to 0.495 V, typ, clamps not added: 24.3 ohm
|   slope of the pullup table from 0 to 0.495 V, typ, clamps not added: 26.7 ohm
|   GND clamp passes 1 mA (typ) near -0.43 V on its own axis
|   rising waveform, R_fixture 50.000, V_fixture 0.0: 20-80 % time 237ps typ, 319ps min, 142ps max; typ from 0 V to 1.96 V
|   rising waveform, R_fixture 50.000, V_fixture 3.300: 20-80 % time 153ps typ, 227ps min, 91.6ps max; typ from 1.28 V to 3.3 V
|   falling waveform, R_fixture 50.000, V_fixture 3.300: 20-80 % time 257ps typ, 327ps min, 180ps max; typ from 3.3 V to 1.28 V
|   falling waveform, R_fixture 50.000, V_fixture 0.0: 20-80 % time 133ps typ, 195ps min, 91.8ps max; typ from 1.96 V to 0 V
[Pulldown]
|Voltage   I(typ)   I(min)   I(max)
-3.3V     -29.32mA   -17.9mA    -45.21mA
-900mV    -29.32mA   -17.9mA    -45.21mA
-500mV    -22.04mA   -15.61mA   -31.59mA
600mV     23.9mA     16.31mA    35.23mA
1.2V      38.8mA     26.54mA    56.81mA
1.9V      44.78mA    31.05mA    64.46mA
3.5V      47.95mA    33.48mA    68.37mA
4V        53.79mA    42.74mA    71.38mA
4.7V      83.76mA    65.34mA    114.8mA
5.3V      118.2mA    90.43mA    168.1mA
5.9V      161.7mA    120.6mA    237.3mA
6.6V      222.4mA    159.9mA    336.1mA
[Pullup]
|Voltage   I(typ)   I(min)   I(max)
-3.3V     212.4mA    158.2mA    332.3mA
-2.9V     187.3mA    140.6mA    297.2mA
-2.6V     167.7mA    126.4mA    267.5mA
-1V       57.61mA    43.97mA    90.57mA
-600mV    29.05mA    23.05mA    44.17mA
-500mV    22.93mA    18.07mA    34.79mA
200mV     -8.086mA   -6.051mA   -12.55mA
800mV     -27.53mA   -20.35mA   -43.24mA
1.5V      -41.6mA    -30.18mA   -66.6mA
2.2V      -47.34mA   -33.6mA    -77.7mA
3.7V      -50.76mA   -35.84mA   -84.41mA
6.6V      -55.19mA   -38.7mA    -92.41mA
[GND_clamp]
|Voltage   I(typ)   I(min)   I(max)
-3.3V     -4.507A    -3.482A    -6.263A
-1.089V   -398.4mA   -420.6mA   -374.7mA
-1.022V   -290.7mA   -338.6mA   -230.6mA
-955mV    -191.4mA   -260.2mA   -120.1mA
-888mV    -107.5mA   -187mA     -73.69mA
-821mV    -53mA      -121.4mA   -59.83mA
-754mV    -31.41mA   -66.95mA   -47.44mA
-687mV    -21.17mA   -28.83mA   -34.23mA
-620mV    -13.21mA   -10.24mA   -21.98mA
-553mV    -6.877mA   -3.592mA   -11.71mA
-352mV    -122.8uA   -54.62uA   -209.3uA
3.3V      0A         0A         0A
[POWER_clamp]
|Voltage   I(typ)   I(min)   I(max)
-3.3V     530uA      347.3uA    956.2uA
-2.663V   63.57uA    15.44uA    254.2uA
-2.529V   27.42uA    10.98uA    148.7uA
-2.328V   15.78uA    8.532uA    64.82uA
-1.725V   7.398uA    3.713uA    31uA
-1.189V   2.659uA    1.053uA    15.99uA
-988mV    1.516uA    474.5nA    11.83uA
-519mV    357.5nA    63.28nA    5.567uA
-251mV    319nA      55.54nA    5.047uA
-50mV     187.6nA    55.54nA    2.655uA
352mV     56.19nA    7.349nA    1.154uA
3.3V      0A         0A         0A
[Ramp]
| variable   typ   min   max
dV/dt_r   1.175/0.235n   0.929/0.316n   1.501/0.142n
dV/dt_f   1.213/0.261n   0.904/0.317n   1.510/0.182n
R_load = 50.000
[Rising Waveform]
R_fixture= 50.000
V_fixture= 0.0
V_fixture_min= 0.0
V_fixture_max= 0.0
|time   V(typ)   V(min)   V(max)
0s        16.97nV    43.8nV     216.8nV
561ps     39.36uV    -3.611uV   -26.62mV
734ps     136.8uV    -3.611uV   1.884V
940ps     -39.36mV   88.47uV    2.353V
1.145ns   1.193V     359.3uV    2.434V
1.303ns   1.646V     -9.936mV   2.462V
1.533ns   1.83V      23.87mV    2.483V
2.008ns   1.923V     1.32V      2.498V
2.873ns   1.955V     1.518V     2.502V
20ns      1.959V     1.548V     2.502V
[Rising Waveform]
R_fixture= 50.000
V_fixture= 3.300
V_fixture_min= 3.140
V_fixture_max= 3.470
|time   V(typ)   V(min)   V(max)
0s        1.278V     1.633V     953.3mV
517ps     1.278V     1.633V     976.5mV
559ps     1.278V     1.633V     1.299V
664ps     1.279V     1.633V     2.993V
822ps     1.28V      1.633V     3.374V
1.065ns   2.902V     1.635V     3.433V
1.321ns   3.234V     1.686V     3.454V
1.668ns   3.275V     2.94V      3.464V
2.05ns    3.291V     3.107V     3.468V
20ns      3.3V       3.14V      3.47V
[Falling Waveform]
R_fixture= 50.000
V_fixture= 3.300
V_fixture_min= 3.140
V_fixture_max= 3.470
|time   V(typ)   V(min)   V(max)
0s        3.3V       3.14V      3.47V
563ps     3.3V       3.14V      3.52V
753ps     3.3V       3.14V      1.697V
962ps     3.355V     3.14V      1.116V
1.301ns   1.692V     3.14V      989.4mV
1.615ns   1.39V      3.182V     965.3mV
1.878ns   1.327V     2.229V     958.3mV
2.12ns    1.303V     1.856V     955.3mV
2.875ns   1.282V     1.664V     953.3mV
20ns      1.278V     1.633V     953.2mV
[Falling Waveform]
R_fixture= 50.000
V_fixture= 0.0
V_fixture_min= 0.0
V_fixture_max= 0.0
|time   V(typ)   V(min)   V(max)
0s        1.959V     1.548V     2.502V
539ps     1.959V     1.548V     2.481V
696ps     1.959V     1.548V     350.2mV
919ps     1.871V     1.548V     55.21mV
1.046ns   723.2mV    1.548V     32mV
1.168ns   185.1mV    1.548V     19.98mV
1.495ns   30.94mV    1.497V     5.579mV
1.773ns   13.59mV    278mV      2.2mV
2.159ns   4.243mV    31.78mV    557.8uV
20ns      2.581nV    -15.79nV   207.5nV
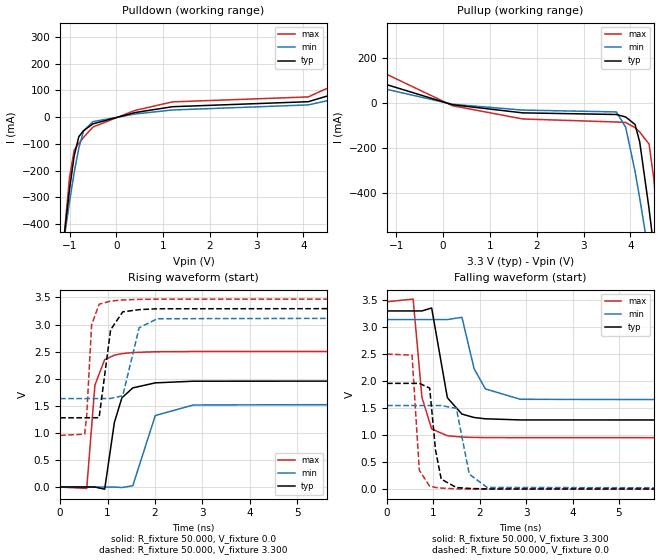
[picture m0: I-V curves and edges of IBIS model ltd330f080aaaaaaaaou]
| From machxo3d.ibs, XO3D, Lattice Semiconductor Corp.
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|   Model ltd330f080aaaaaaaaou
[Model] ltd330f080aaaaaaaaou
Model_type Output
Polarity   Non-Inverting
Enable   Active-High
Vmeas =  1.650V
Cref =  0.0F
Rref =  1.000M
Vref =  0.0V
C_comp   4.200pF   3.800pF   7.500pF
[Temperature Range]   25.000   0.105k   -40.000
[Voltage Range]   3.300V   3.140V   3.470V
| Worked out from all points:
|   slope of the pulldown table from 0 to 0.495 V, typ, clamps not added: 24.3 ohm
|   slope of the pullup table from 0 to 0.495 V, typ, clamps not added: 26.7 ohm
|   rising waveform, R_fixture 50.000, V_fixture 0.0: 20-80 % time 237ps typ, 319ps min, 142ps max; typ from 0 V to 1.96 V
|   rising waveform, R_fixture 50.000, V_fixture 3.300: 20-80 % time 153ps typ, 227ps min, 91.6ps max; typ from 1.28 V to 3.3 V
|   falling waveform, R_fixture 50.000, V_fixture 3.300: 20-80 % time 257ps typ, 327ps min, 180ps max; typ from 3.3 V to 1.28 V
|   falling waveform, R_fixture 50.000, V_fixture 0.0: 20-80 % time 133ps typ, 195ps min, 91.8ps max; typ from 1.96 V to 0 V
[Pulldown]
|Voltage   I(typ)   I(min)   I(max)
-3.3V     -4.507A    -3.482A    -6.263A
-1.1V     -423.4mA   -437.5mA   -416.7mA
-1V       -269.7mA   -316.9mA   -225.1mA
-900mV    -144.5mA   -206.8mA   -123.1mA
-800mV    -72.92mA   -115.2mA   -98.42mA
-700mV    -50.73mA   -52.06mA   -75.89mA
-500mV    -25.36mA   -17.06mA   -37.25mA
400mV     16.94mA    11.56mA    24.96mA
1.2V      38.8mA     26.54mA    56.81mA
4.1V      57.47mA    45.51mA    75.33mA
5.4V      124.9mA    95.12mA    178.6mA
6.6V      222.9mA    160.3mA    336.8mA
[Pullup]
|Voltage   I(typ)   I(min)   I(max)
-3.3V     212.9mA    158.6mA    333.3mA
200mV     -8.086mA   -6.051mA   -12.55mA
1.7V      -44.02mA   -31.73mA   -70.96mA
3.7V      -51.18mA   -39.85mA   -84.43mA
3.9V      -62.28mA   -107.4mA   -86.42mA
4.1V      -95.15mA   -302.3mA   -109.4mA
4.2V      -172.6mA   -421.2mA   -128.8mA
4.4V      -468.8mA   -676.6mA   -181.9mA
4.5V      -639.3mA   -809mA     -333.7mA
4.6V      -815.4mA   -943.4mA   -557.7mA
4.7V      -994.9mA   -1.079A    -803mA
6.6V      -4.562A    -3.748A    -5.893A
[Ramp]
| variable   typ   min   max
dV/dt_r   1.175/0.235n   0.929/0.316n   1.501/0.142n
dV/dt_f   1.213/0.261n   0.904/0.317n   1.510/0.182n
R_load = 50.000
[Rising Waveform]
R_fixture= 50.000
V_fixture= 0.0
V_fixture_min= 0.0
V_fixture_max= 0.0
|time   V(typ)   V(min)   V(max)
0s        16.97nV    43.8nV     216.8nV
561ps     39.35uV    -3.524uV   -26.62mV
734ps     136.8uV    -3.524uV   1.884V
940ps     -39.36mV   88.46uV    2.353V
1.145ns   1.193V     359.3uV    2.434V
1.303ns   1.646V     -9.936mV   2.462V
1.533ns   1.83V      23.87mV    2.483V
2.008ns   1.923V     1.32V      2.498V
2.815ns   1.954V     1.515V     2.502V
20ns      1.959V     1.548V     2.502V
[Rising Waveform]
R_fixture= 50.000
V_fixture= 3.300
V_fixture_min= 3.140
V_fixture_max= 3.470
|time   V(typ)   V(min)   V(max)
0s        1.278V     1.633V     953.3mV
517ps     1.278V     1.633V     976.5mV
559ps     1.278V     1.633V     1.299V
664ps     1.279V     1.633V     2.993V
822ps     1.28V      1.633V     3.374V
1.065ns   2.902V     1.635V     3.433V
1.321ns   3.234V     1.686V     3.454V
1.668ns   3.275V     2.94V      3.464V
2.05ns    3.291V     3.107V     3.468V
20ns      3.3V       3.14V      3.47V
[Falling Waveform]
R_fixture= 50.000
V_fixture= 3.300
V_fixture_min= 3.140
V_fixture_max= 3.470
|time   V(typ)   V(min)   V(max)
0s        3.3V       3.14V      3.47V
563ps     3.3V       3.14V      3.52V
753ps     3.3V       3.14V      1.697V
962ps     3.355V     3.14V      1.116V
1.301ns   1.692V     3.14V      989.4mV
1.615ns   1.39V      3.182V     965.3mV
1.878ns   1.327V     2.229V     958.3mV
2.12ns    1.303V     1.856V     955.3mV
2.875ns   1.282V     1.664V     953.3mV
20ns      1.278V     1.633V     953.2mV
[Falling Waveform]
R_fixture= 50.000
V_fixture= 0.0
V_fixture_min= 0.0
V_fixture_max= 0.0
|time   V(typ)   V(min)   V(max)
0s        1.959V     1.548V     2.502V
539ps     1.959V     1.548V     2.481V
696ps     1.959V     1.548V     350.2mV
919ps     1.871V     1.548V     55.21mV
1.046ns   723.2mV    1.548V     32mV
1.168ns   185.1mV    1.548V     19.98mV
1.495ns   30.94mV    1.497V     5.579mV
1.773ns   13.59mV    278mV      2.2mV
2.159ns   4.243mV    31.78mV    557.8uV
20ns      2.581nV    -15.79nV   207.5nV
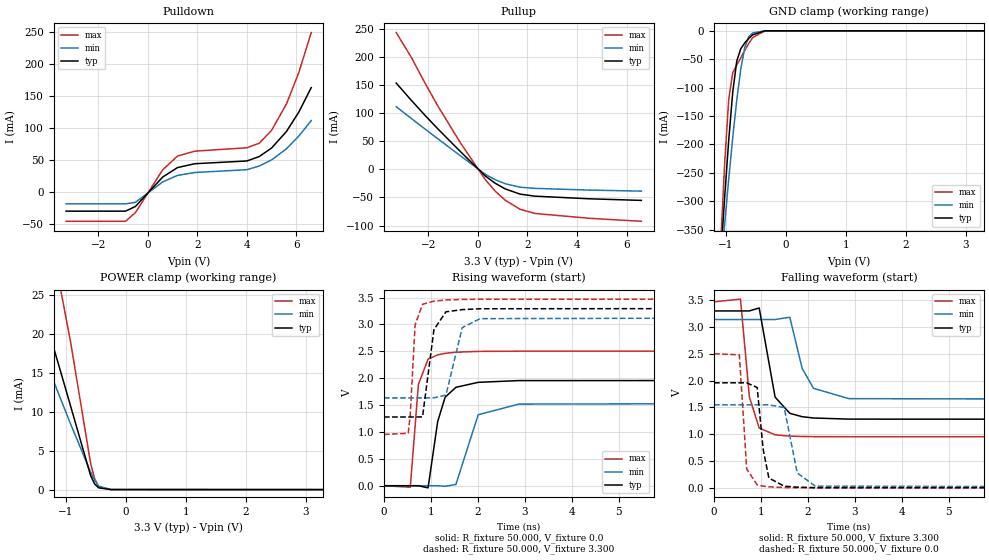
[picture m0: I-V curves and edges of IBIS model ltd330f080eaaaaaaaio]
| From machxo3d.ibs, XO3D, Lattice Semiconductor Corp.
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|   Model ltd330f080eaaaaaaaio
[Model] ltd330f080eaaaaaaaio
Model_type I/O
Polarity   Non-Inverting
Enable   Active-Low
Vinl =  0.800V
Vinh =  2.000V
Vmeas =  1.650V
Cref =  0.0F
Rref =  1.000M
Vref =  0.0V
C_comp   4.200pF   3.800pF   7.500pF
[Temperature Range]   25.000   0.105k   -40.000
[Voltage Range]   3.300V   3.140V   3.470V
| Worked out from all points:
|   slope of the pulldown table from 0 to 0.495 V, typ, clamps not added: 24.3 ohm
|   slope of the pullup table from 0 to 0.495 V, typ, clamps not added: 26.7 ohm
|   GND clamp passes 1 mA (typ) near -0.43 V on its own axis
|   POWER clamp passes 1 mA (typ) near -0.54 V on its own axis
|   rising waveform, R_fixture 50.000, V_fixture 0.0: 20-80 % time 237ps typ, 319ps min, 142ps max; typ from 0 V to 1.96 V
|   rising waveform, R_fixture 50.000, V_fixture 3.300: 20-80 % time 153ps typ, 227ps min, 91.6ps max; typ from 1.28 V to 3.3 V
|   falling waveform, R_fixture 50.000, V_fixture 3.300: 20-80 % time 257ps typ, 327ps min, 180ps max; typ from 3.3 V to 1.28 V
|   falling waveform, R_fixture 50.000, V_fixture 0.0: 20-80 % time 133ps typ, 195ps min, 91.8ps max; typ from 1.96 V to 0 V
[Pulldown]
|Voltage   I(typ)   I(min)   I(max)
-3.3V     -29.32mA   -17.9mA    -45.21mA
-900mV    -29.32mA   -17.9mA    -45.21mA
-500mV    -22.04mA   -15.61mA   -31.59mA
600mV     23.9mA     16.31mA    35.23mA
1.2V      38.8mA     26.54mA    56.81mA
1.9V      44.78mA    31.05mA    64.46mA
4V        49.1mA     35.45mA    69.72mA
4.5V      56.03mA    41.15mA    76.83mA
5V        69.38mA    50.78mA    97mA
5.6V      95.22mA    68.23mA    138.3mA
6.1V      125.6mA    88.08mA    187.6mA
6.6V      163.8mA    112.2mA    249.8mA
[Pullup]
|Voltage   I(typ)   I(min)   I(max)
-3.3V     153.7mA    111.6mA    243.6mA
-2.7V     123.5mA    90.98mA    200.3mA
-2.1V     94.47mA    70.64mA    150.5mA
-1.6V     71.33mA    53.89mA    111.6mA
-700mV    31.42mA    23.96mA    46.76mA
300mV     -11.82mA   -8.831mA   -18.38mA
700mV     -24.77mA   -18.36mA   -38.83mA
1.1V      -34.65mA   -25.44mA   -54.83mA
1.7V      -44.02mA   -31.73mA   -70.96mA
2.3V      -47.66mA   -33.79mA   -78.43mA
4.5V      -52.35mA   -36.84mA   -87.07mA
6.6V      -55.19mA   -38.7mA    -92.41mA
[GND_clamp]
|Voltage   I(typ)   I(min)   I(max)
-3.3V     -4.507A    -3.482A    -6.263A
-1.089V   -398.4mA   -420.6mA   -374.7mA
-1.022V   -290.7mA   -338.6mA   -230.6mA
-955mV    -191.4mA   -260.2mA   -120.1mA
-888mV    -107.5mA   -187mA     -73.69mA
-821mV    -53mA      -121.4mA   -59.83mA
-754mV    -31.41mA   -66.95mA   -47.44mA
-687mV    -21.17mA   -28.83mA   -34.23mA
-620mV    -13.21mA   -10.24mA   -21.98mA
-553mV    -6.877mA   -3.592mA   -11.71mA
-352mV    -122.8uA   -54.62uA   -209.3uA
3.3V      0A         0A         0A
[POWER_clamp]
|Voltage   I(typ)   I(min)   I(max)
-3.3V     59.07mA    46.89mA    89.53mA
-1.993V   37.2mA     28.86mA    58.21mA
-1.926V   35.72mA    27.66mA    56.06mA
-1.591V   27.94mA    21.43mA    44.69mA
-1.189V   17.87mA    13.66mA    29.79mA
-1.122V   16.12mA    12.35mA    27.17mA
-921mV    10.77mA    8.455mA    19.02mA
-586mV    1.798mA    2.256mA    3.367mA
-519mV    726.5uA    1.214mA    1.405mA
-452mV    229.1uA    443uA      409.2uA
-251mV    5.569uA    5.296uA    9.168uA
3.3V      0A         0A         0A
[Ramp]
| variable   typ   min   max
dV/dt_r   1.175/0.235n   0.929/0.316n   1.501/0.142n
dV/dt_f   1.213/0.261n   0.904/0.317n   1.510/0.182n
R_load = 50.000
[Rising Waveform]
R_fixture= 50.000
V_fixture= 0.0
V_fixture_min= 0.0
V_fixture_max= 0.0
|time   V(typ)   V(min)   V(max)
0s        16.97nV    43.8nV     216.8nV
561ps     39.36uV    -3.611uV   -26.62mV
734ps     136.8uV    -3.611uV   1.884V
940ps     -39.36mV   88.47uV    2.353V
1.145ns   1.193V     359.3uV    2.434V
1.303ns   1.646V     -9.936mV   2.462V
1.533ns   1.83V      23.87mV    2.483V
2.008ns   1.923V     1.32V      2.498V
2.873ns   1.955V     1.518V     2.502V
20ns      1.959V     1.548V     2.502V
[Rising Waveform]
R_fixture= 50.000
V_fixture= 3.300
V_fixture_min= 3.140
V_fixture_max= 3.470
|time   V(typ)   V(min)   V(max)
0s        1.278V     1.633V     953.3mV
517ps     1.278V     1.633V     976.5mV
559ps     1.278V     1.633V     1.299V
664ps     1.279V     1.633V     2.993V
822ps     1.28V      1.633V     3.374V
1.065ns   2.902V     1.635V     3.433V
1.321ns   3.234V     1.686V     3.454V
1.668ns   3.275V     2.94V      3.464V
2.05ns    3.291V     3.107V     3.468V
20ns      3.3V       3.14V      3.47V
[Falling Waveform]
R_fixture= 50.000
V_fixture= 3.300
V_fixture_min= 3.140
V_fixture_max= 3.470
|time   V(typ)   V(min)   V(max)
0s        3.3V       3.14V      3.47V
563ps     3.3V       3.14V      3.52V
753ps     3.3V       3.14V      1.697V
962ps     3.355V     3.14V      1.116V
1.301ns   1.692V     3.14V      989.4mV
1.615ns   1.39V      3.182V     965.3mV
1.878ns   1.327V     2.229V     958.3mV
2.12ns    1.303V     1.856V     955.3mV
2.875ns   1.282V     1.664V     953.3mV
20ns      1.278V     1.633V     953.2mV
[Falling Waveform]
R_fixture= 50.000
V_fixture= 0.0
V_fixture_min= 0.0
V_fixture_max= 0.0
|time   V(typ)   V(min)   V(max)
0s        1.959V     1.548V     2.502V
539ps     1.959V     1.548V     2.481V
696ps     1.959V     1.548V     350.2mV
919ps     1.871V     1.548V     55.21mV
1.046ns   723.2mV    1.548V     32mV
1.168ns   185.1mV    1.548V     19.98mV
1.495ns   30.94mV    1.497V     5.579mV
1.773ns   13.59mV    278mV      2.2mV
2.159ns   4.243mV    31.78mV    557.8uV
20ns      2.581nV    -15.79nV   207.5nV
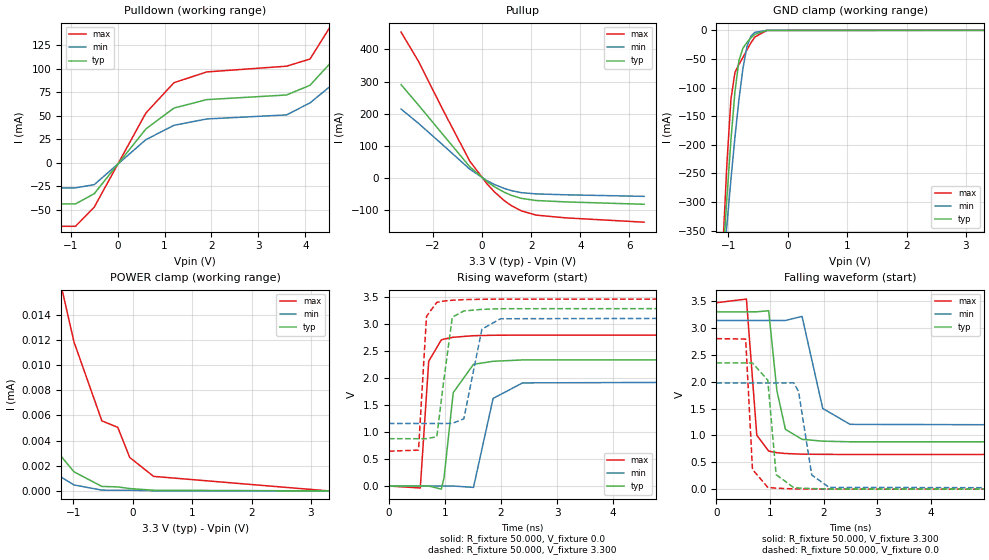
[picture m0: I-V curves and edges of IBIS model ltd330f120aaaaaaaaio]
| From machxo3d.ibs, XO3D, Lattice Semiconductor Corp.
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|   Model ltd330f120aaaaaaaaio
[Model] ltd330f120aaaaaaaaio
Model_type I/O
Polarity   Non-Inverting
Enable   Active-Low
Vinl =  0.800V
Vinh =  2.000V
Vmeas =  1.650V
Cref =  0.0F
Rref =  1.000M
Vref =  0.0V
C_comp   4.200pF   3.800pF   7.500pF
[Temperature Range]   25.000   0.105k   -40.000
[Voltage Range]   3.300V   3.140V   3.470V
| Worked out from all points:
|   slope of the pulldown table from 0 to 0.495 V, typ, clamps not added: 16.2 ohm
|   slope of the pullup table from 0 to 0.495 V, typ, clamps not added: 17.8 ohm
|   GND clamp passes 1 mA (typ) near -0.43 V on its own axis
|   rising waveform, R_fixture 50.000, V_fixture 0.0: 20-80 % time 164ps typ, 240ps min, 95.6ps max; typ from 0 V to 2.35 V
|   rising waveform, R_fixture 50.000, V_fixture 3.300: 20-80 % time 128ps typ, 207ps min, 72.2ps max; typ from 0.878 V to 3.3 V
|   falling waveform, R_fixture 50.000, V_fixture 3.300: 20-80 % time 173ps typ, 256ps min, 113ps max; typ from 3.3 V to 0.878 V
|   falling waveform, R_fixture 50.000, V_fixture 0.0: 20-80 % time 106ps typ, 166ps min, 71.1ps max; typ from 2.35 V to 0 V
[Pulldown]
|Voltage   I(typ)   I(min)   I(max)
-3.3V     -43.98mA   -26.85mA   -67.81mA
-900mV    -43.98mA   -26.85mA   -67.81mA
-500mV    -33.06mA   -23.42mA   -47.39mA
600mV     35.86mA    24.47mA    52.84mA
1.2V      58.2mA     39.81mA    85.22mA
1.9V      67.18mA    46.57mA    96.69mA
3.6V      72.12mA    50.9mA     102.8mA
4.1V      82.46mA    63.67mA    110.4mA
4.8V      120.5mA    92.38mA    166.3mA
5.4V      167.5mA    125.9mA    239.7mA
6V        229.2mA    167.9mA    338.6mA
6.6V      304.3mA    215.9mA    460.9mA
[Pullup]
|Voltage   I(typ)   I(min)   I(max)
-3.3V     290.3mA    214.3mA    454.2mA
-2.6V     227.5mA    170.3mA    364.3mA
-1.6V     135.2mA    102.5mA    212.5mA
-500mV    34.13mA    26.63mA    51.68mA
200mV     -12.13mA   -9.077mA   -18.82mA
500mV     -28.04mA   -20.86mA   -43.76mA
900mV     -45.13mA   -33.29mA   -71.06mA
1.2V      -54.99mA   -40.25mA   -87.25mA
1.6V      -64.35mA   -46.53mA   -103.4mA
2.2V      -71.02mA   -50.4mA    -116.5mA
3.4V      -75.29mA   -53.18mA   -125.1mA
6.6V      -82.78mA   -58.05mA   -138.6mA
[GND_clamp]
|Voltage   I(typ)   I(min)   I(max)
-3.3V     -4.507A    -3.482A    -6.263A
-1.089V   -398.4mA   -420.6mA   -374.7mA
-1.022V   -290.7mA   -338.6mA   -230.6mA
-955mV    -191.4mA   -260.2mA   -120.1mA
-888mV    -107.5mA   -187mA     -73.69mA
-821mV    -53mA      -121.4mA   -59.83mA
-754mV    -31.41mA   -66.95mA   -47.44mA
-687mV    -21.17mA   -28.83mA   -34.23mA
-620mV    -13.21mA   -10.24mA   -21.98mA
-553mV    -6.877mA   -3.592mA   -11.71mA
-352mV    -122.8uA   -54.62uA   -209.3uA
3.3V      0A         0A         0A
[POWER_clamp]
|Voltage   I(typ)   I(min)   I(max)
-3.3V     530uA      347.3uA    956.2uA
-2.663V   63.57uA    15.44uA    254.2uA
-2.529V   27.42uA    10.98uA    148.7uA
-2.328V   15.78uA    8.532uA    64.82uA
-1.725V   7.398uA    3.713uA    31uA
-1.189V   2.659uA    1.053uA    15.99uA
-988mV    1.516uA    474.5nA    11.83uA
-519mV    357.5nA    63.28nA    5.567uA
-251mV    319nA      55.54nA    5.047uA
-50mV     187.6nA    55.54nA    2.655uA
352mV     56.19nA    7.349nA    1.154uA
3.3V      0A         0A         0A
[Ramp]
| variable   typ   min   max
dV/dt_r   1.409/0.163n   1.186/0.238n   1.681/95.274p
dV/dt_f   1.453/0.173n   1.187/0.255n   1.695/0.113n
R_load = 50.000
[Rising Waveform]
R_fixture= 50.000
V_fixture= 0.0
V_fixture_min= 0.0
V_fixture_max= 0.0
|time   V(typ)   V(min)   V(max)
0s        12.56nV    33.46nV    156.1nV
560ps     37.39uV    -6.058uV   -36.6mV
710ps     137.4uV    -6.058uV   2.316V
935ps     -58.58mV   73.02uV    2.712V
984ps     154.4mV    110.9uV    2.727V
1.148ns   1.734V     138.9uV    2.761V
1.509ns   2.259V     -25.88mV   2.79V
1.859ns   2.315V     1.626V     2.798V
2.385ns   2.34V      1.914V     2.801V
20ns      2.349V     1.976V     2.802V
[Rising Waveform]
R_fixture= 50.000
V_fixture= 3.300
V_fixture_min= 3.140
V_fixture_max= 3.470
|time   V(typ)   V(min)   V(max)
0s        878.1mV    1.161V     645.8mV
528ps     878.1mV    1.161V     666.3mV
671ps     878.8mV    1.161V     3.149V
855ps     914.5mV    1.161V     3.409V
972ps     1.903V     1.161V     3.432V
1.131ns   3.134V     1.162V     3.448V
1.337ns   3.249V     1.247V     3.459V
1.659ns   3.279V     2.91V      3.466V
1.991ns   3.291V     3.105V     3.469V
20ns      3.3V       3.14V      3.47V
[Falling Waveform]
R_fixture= 50.000
V_fixture= 3.300
V_fixture_min= 3.140
V_fixture_max= 3.470
|time   V(typ)   V(min)   V(max)
0s        3.3V       3.14V      3.47V
560ps     3.3V       3.14V      3.538V
753ps     3.301V     3.14V      1.005V
975ps     3.321V     3.14V      708.4mV
1.128ns   1.833V     3.139V     679.1mV
1.287ns   1.114V     3.14V      663.7mV
1.597ns   927.3mV    3.215V     651.7mV
1.983ns   893.5mV    1.503V     647.6mV
2.493ns   881.6mV    1.206V     646mV
20ns      878mV      1.161V     645.7mV
[Falling Waveform]
R_fixture= 50.000
V_fixture= 0.0
V_fixture_min= 0.0
V_fixture_max= 0.0
|time   V(typ)   V(min)   V(max)
0s        2.349V     1.976V     2.802V
546ps     2.349V     1.976V     2.793V
673ps     2.349V     1.976V     367.2mV
958ps     2.028V     1.976V     33.51mV
1.114ns   270mV      1.976V     18.29mV
1.44ns    29.93mV    1.979V     5.192mV
1.532ns   21.95mV    1.819V     3.774mV
1.778ns   10.88mV    263.4mV    1.393mV
2.102ns   3.957mV    33.01mV    432.8uV
20ns      -191.1nV   29.53nV    104.6nV
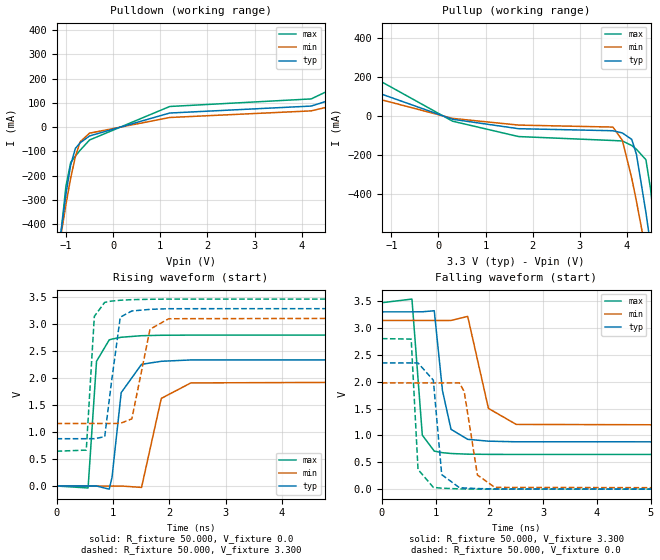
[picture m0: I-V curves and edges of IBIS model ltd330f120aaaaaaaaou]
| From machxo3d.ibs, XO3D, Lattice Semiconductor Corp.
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|   Model ltd330f120aaaaaaaaou
[Model] ltd330f120aaaaaaaaou
Model_type Output
Polarity   Non-Inverting
Enable   Active-High
Vmeas =  1.650V
Cref =  0.0F
Rref =  1.000M
Vref =  0.0V
C_comp   4.200pF   3.800pF   7.500pF
[Temperature Range]   25.000   0.105k   -40.000
[Voltage Range]   3.300V   3.140V   3.470V
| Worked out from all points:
|   slope of the pulldown table from 0 to 0.495 V, typ, clamps not added: 16.2 ohm
|   slope of the pullup table from 0 to 0.495 V, typ, clamps not added: 17.8 ohm
|   rising waveform, R_fixture 50.000, V_fixture 0.0: 20-80 % time 164ps typ, 240ps min, 95.6ps max; typ from 0 V to 2.35 V
|   rising waveform, R_fixture 50.000, V_fixture 3.300: 20-80 % time 128ps typ, 207ps min, 72.2ps max; typ from 0.878 V to 3.3 V
|   falling waveform, R_fixture 50.000, V_fixture 3.300: 20-80 % time 173ps typ, 256ps min, 113ps max; typ from 3.3 V to 0.878 V
|   falling waveform, R_fixture 50.000, V_fixture 0.0: 20-80 % time 106ps typ, 166ps min, 71.1ps max; typ from 2.35 V to 0 V
[Pulldown]
|Voltage   I(typ)   I(min)   I(max)
-3.3V     -4.507A    -3.483A    -6.263A
-1.1V     -426.7mA   -439mA     -425mA
-1V       -276.1mA   -319.1mA   -243.2mA
-900mV    -156.3mA   -210.3mA   -145.7mA
-800mV    -87.58mA   -121.4mA   -119.6mA
-700mV    -64.66mA   -60.75mA   -95.46mA
-500mV    -36.38mA   -24.87mA   -53.05mA
1.2V      58.2mA     39.81mA    85.22mA
4.2V      86.95mA    67.09mA    116.4mA
5.1V      142.2mA    108.1mA    199.9mA
6.4V      278.4mA    199.8mA    418.6mA
6.6V      304.8mA    216.4mA    461.6mA
[Pullup]
|Voltage   I(typ)   I(min)   I(max)
-3.3V     290.8mA    214.7mA    455.2mA
300mV     -17.73mA   -13.25mA   -27.57mA
1.7V      -66.04mA   -47.59mA   -106.4mA
3.7V      -76.56mA   -57.77mA   -126.6mA
3.9V      -87.85mA   -125.4mA   -129mA
4.1V      -120.9mA   -320.5mA   -152.3mA
4.2V      -198.5mA   -439.5mA   -171.8mA
4.4V      -494.9mA   -694.9mA   -225.2mA
4.5V      -665.5mA   -827.4mA   -377.2mA
4.6V      -841.6mA   -961.9mA   -601.4mA
4.7V      -1.021A    -1.098A    -846.9mA
6.6V      -4.589A    -3.768A    -5.939A
[Ramp]
| variable   typ   min   max
dV/dt_r   1.409/0.163n   1.186/0.238n   1.681/95.274p
dV/dt_f   1.453/0.173n   1.187/0.255n   1.695/0.113n
R_load = 50.000
[Rising Waveform]
R_fixture= 50.000
V_fixture= 0.0
V_fixture_min= 0.0
V_fixture_max= 0.0
|time   V(typ)   V(min)   V(max)
0s        12.56nV    33.46nV    156.1nV
560ps     39.25uV    -6.037uV   -36.6mV
710ps     137.4uV    -6.037uV   2.316V
935ps     -58.58mV   73.01uV    2.712V
984ps     154.4mV    110.9uV    2.727V
1.148ns   1.734V     138.9uV    2.761V
1.509ns   2.259V     -25.88mV   2.79V
1.859ns   2.315V     1.626V     2.798V
2.385ns   2.34V      1.914V     2.801V
20ns      2.349V     1.976V     2.802V
[Rising Waveform]
R_fixture= 50.000
V_fixture= 3.300
V_fixture_min= 3.140
V_fixture_max= 3.470
|time   V(typ)   V(min)   V(max)
0s        878.1mV    1.161V     645.8mV
528ps     878.1mV    1.161V     666.3mV
671ps     878.8mV    1.161V     3.149V
855ps     914.5mV    1.161V     3.409V
972ps     1.903V     1.161V     3.432V
1.131ns   3.134V     1.162V     3.448V
1.337ns   3.249V     1.247V     3.459V
1.659ns   3.279V     2.91V      3.466V
1.991ns   3.291V     3.105V     3.469V
20ns      3.3V       3.14V      3.47V
[Falling Waveform]
R_fixture= 50.000
V_fixture= 3.300
V_fixture_min= 3.140
V_fixture_max= 3.470
|time   V(typ)   V(min)   V(max)
0s        3.3V       3.14V      3.47V
560ps     3.3V       3.14V      3.538V
753ps     3.301V     3.14V      1.005V
975ps     3.321V     3.14V      708.4mV
1.128ns   1.833V     3.139V     679.1mV
1.287ns   1.114V     3.14V      663.7mV
1.597ns   927.3mV    3.215V     651.7mV
1.983ns   893.5mV    1.503V     647.6mV
2.5ns     881.6mV    1.205V     646mV
20ns      878mV      1.161V     645.7mV
[Falling Waveform]
R_fixture= 50.000
V_fixture= 0.0
V_fixture_min= 0.0
V_fixture_max= 0.0
|time   V(typ)   V(min)   V(max)
0s        2.349V     1.976V     2.802V
546ps     2.349V     1.976V     2.793V
673ps     2.349V     1.976V     367.2mV
958ps     2.028V     1.976V     33.51mV
1.114ns   270mV      1.976V     18.29mV
1.44ns    29.93mV    1.979V     5.192mV
1.532ns   21.95mV    1.819V     3.774mV
1.778ns   10.88mV    263.4mV    1.393mV
2.102ns   3.957mV    33.01mV    432.8uV
20ns      -191.1nV   29.53nV    104.6nV
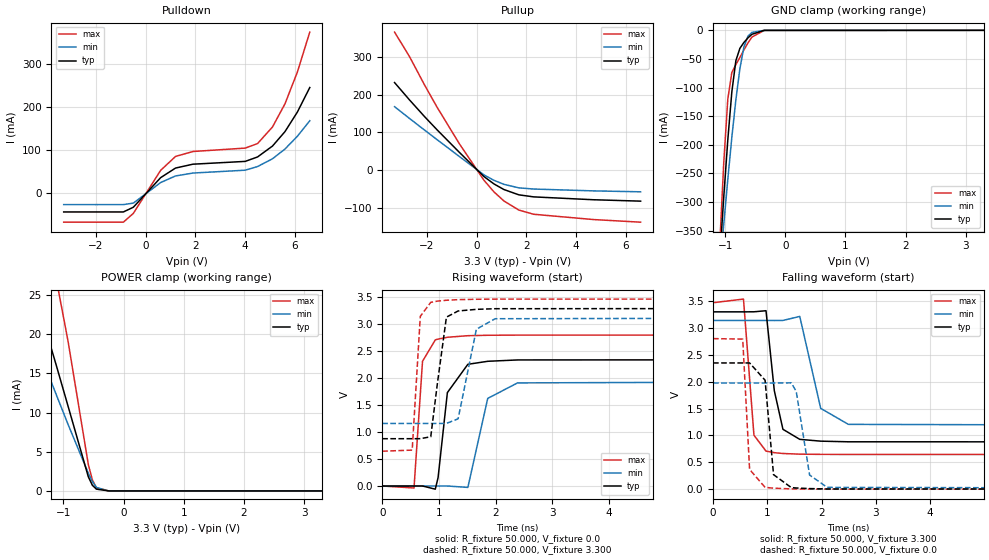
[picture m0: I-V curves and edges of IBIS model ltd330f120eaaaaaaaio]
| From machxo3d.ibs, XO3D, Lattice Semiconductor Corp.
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|   Model ltd330f120eaaaaaaaio
[Model] ltd330f120eaaaaaaaio
Model_type I/O
Polarity   Non-Inverting
Enable   Active-Low
Vinl =  0.800V
Vinh =  2.000V
Vmeas =  1.650V
Cref =  0.0F
Rref =  1.000M
Vref =  0.0V
C_comp   4.200pF   3.800pF   7.500pF
[Temperature Range]   25.000   0.105k   -40.000
[Voltage Range]   3.300V   3.140V   3.470V
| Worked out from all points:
|   slope of the pulldown table from 0 to 0.495 V, typ, clamps not added: 16.2 ohm
|   slope of the pullup table from 0 to 0.495 V, typ, clamps not added: 17.8 ohm
|   GND clamp passes 1 mA (typ) near -0.43 V on its own axis
|   POWER clamp passes 1 mA (typ) near -0.54 V on its own axis
|   rising waveform, R_fixture 50.000, V_fixture 0.0: 20-80 % time 164ps typ, 240ps min, 95.6ps max; typ from 0 V to 2.35 V
|   rising waveform, R_fixture 50.000, V_fixture 3.300: 20-80 % time 128ps typ, 207ps min, 72.2ps max; typ from 0.878 V to 3.3 V
|   falling waveform, R_fixture 50.000, V_fixture 3.300: 20-80 % time 173ps typ, 256ps min, 113ps max; typ from 3.3 V to 0.878 V
|   falling waveform, R_fixture 50.000, V_fixture 0.0: 20-80 % time 106ps typ, 166ps min, 71.1ps max; typ from 2.35 V to 0 V
[Pulldown]
|Voltage   I(typ)   I(min)   I(max)
-3.3V     -43.98mA   -26.85mA   -67.81mA
-900mV    -43.98mA   -26.85mA   -67.81mA
-500mV    -33.06mA   -23.42mA   -47.39mA
600mV     35.86mA    24.47mA    52.84mA
1.2V      58.2mA     39.81mA    85.22mA
1.9V      67.18mA    46.57mA    96.69mA
4V        73.65mA    53.18mA    104.6mA
4.5V      84.05mA    61.72mA    115.2mA
5.1V      109.4mA    79.84mA    153.8mA
5.6V      142.8mA    102.3mA    207.4mA
6.1V      188.4mA    132.1mA    281.4mA
6.6V      245.6mA    168.3mA    374.6mA
[Pullup]
|Voltage   I(typ)   I(min)   I(max)
-3.3V     231.7mA    167.7mA    365.5mA
-2.7V     185.8mA    136.6mA    300.8mA
-2.1V     141.9mA    106mA      226.2mA
-1.6V     107.1mA    80.87mA    167.6mA
-700mV    47.13mA    35.94mA    70.14mA
300mV     -17.73mA   -13.25mA   -27.57mA
700mV     -37.16mA   -27.54mA   -58.24mA
1.1V      -51.98mA   -38.15mA   -82.25mA
1.7V      -66.04mA   -47.59mA   -106.4mA
2.3V      -71.49mA   -50.69mA   -117.6mA
4.7V      -79.06mA   -55.58mA   -131.6mA
6.6V      -82.78mA   -58.05mA   -138.6mA
[GND_clamp]
|Voltage   I(typ)   I(min)   I(max)
-3.3V     -4.507A    -3.482A    -6.263A
-1.089V   -398.4mA   -420.6mA   -374.7mA
-1.022V   -290.7mA   -338.6mA   -230.6mA
-955mV    -191.4mA   -260.2mA   -120.1mA
-888mV    -107.5mA   -187mA     -73.69mA
-821mV    -53mA      -121.4mA   -59.83mA
-754mV    -31.41mA   -66.95mA   -47.44mA
-687mV    -21.17mA   -28.83mA   -34.23mA
-620mV    -13.21mA   -10.24mA   -21.98mA
-553mV    -6.877mA   -3.592mA   -11.71mA
-352mV    -122.8uA   -54.62uA   -209.3uA
3.3V      0A         0A         0A
[POWER_clamp]
|Voltage   I(typ)   I(min)   I(max)
-3.3V     59.07mA    46.89mA    89.53mA
-1.993V   37.2mA     28.86mA    58.21mA
-1.926V   35.72mA    27.66mA    56.06mA
-1.591V   27.94mA    21.43mA    44.69mA
-1.189V   17.87mA    13.66mA    29.79mA
-1.122V   16.12mA    12.35mA    27.17mA
-921mV    10.77mA    8.455mA    19.02mA
-586mV    1.798mA    2.256mA    3.367mA
-519mV    726.5uA    1.214mA    1.405mA
-452mV    229.1uA    443uA      409.2uA
-251mV    5.569uA    5.296uA    9.168uA
3.3V      0A         0A         0A
[Ramp]
| variable   typ   min   max
dV/dt_r   1.409/0.163n   1.186/0.238n   1.681/95.274p
dV/dt_f   1.453/0.173n   1.187/0.255n   1.695/0.113n
R_load = 50.000
[Rising Waveform]
R_fixture= 50.000
V_fixture= 0.0
V_fixture_min= 0.0
V_fixture_max= 0.0
|time   V(typ)   V(min)   V(max)
0s        12.56nV    33.46nV    156.1nV
560ps     37.38uV    -6.059uV   -36.6mV
710ps     137.4uV    -6.059uV   2.316V
935ps     -58.57mV   73.02uV    2.712V
984ps     154.4mV    110.9uV    2.727V
1.148ns   1.734V     138.8uV    2.761V
1.509ns   2.259V     -25.88mV   2.79V
1.859ns   2.315V     1.626V     2.798V
2.385ns   2.34V      1.914V     2.801V
20ns      2.349V     1.976V     2.802V
[Rising Waveform]
R_fixture= 50.000
V_fixture= 3.300
V_fixture_min= 3.140
V_fixture_max= 3.470
|time   V(typ)   V(min)   V(max)
0s        878.1mV    1.161V     645.8mV
528ps     878.1mV    1.161V     666.3mV
671ps     878.8mV    1.161V     3.149V
855ps     914.5mV    1.161V     3.409V
972ps     1.903V     1.161V     3.432V
1.131ns   3.134V     1.162V     3.448V
1.337ns   3.249V     1.247V     3.459V
1.659ns   3.279V     2.91V      3.466V
1.991ns   3.291V     3.105V     3.469V
20ns      3.3V       3.14V      3.47V
[Falling Waveform]
R_fixture= 50.000
V_fixture= 3.300
V_fixture_min= 3.140
V_fixture_max= 3.470
|time   V(typ)   V(min)   V(max)
0s        3.3V       3.14V      3.47V
560ps     3.3V       3.14V      3.538V
753ps     3.301V     3.14V      1.005V
975ps     3.321V     3.14V      708.4mV
1.128ns   1.833V     3.139V     679.1mV
1.287ns   1.114V     3.14V      663.7mV
1.597ns   927.3mV    3.215V     651.7mV
1.983ns   893.5mV    1.503V     647.6mV
2.493ns   881.6mV    1.206V     646mV
20ns      878mV      1.161V     645.7mV
[Falling Waveform]
R_fixture= 50.000
V_fixture= 0.0
V_fixture_min= 0.0
V_fixture_max= 0.0
|time   V(typ)   V(min)   V(max)
0s        2.349V     1.976V     2.802V
546ps     2.349V     1.976V     2.793V
673ps     2.349V     1.976V     367.2mV
958ps     2.028V     1.976V     33.51mV
1.114ns   270mV      1.976V     18.29mV
1.44ns    29.93mV    1.979V     5.192mV
1.532ns   21.95mV    1.819V     3.774mV
1.778ns   10.88mV    263.4mV    1.393mV
2.102ns   3.957mV    33.01mV    432.8uV
20ns      -191.1nV   29.53nV    104.6nV
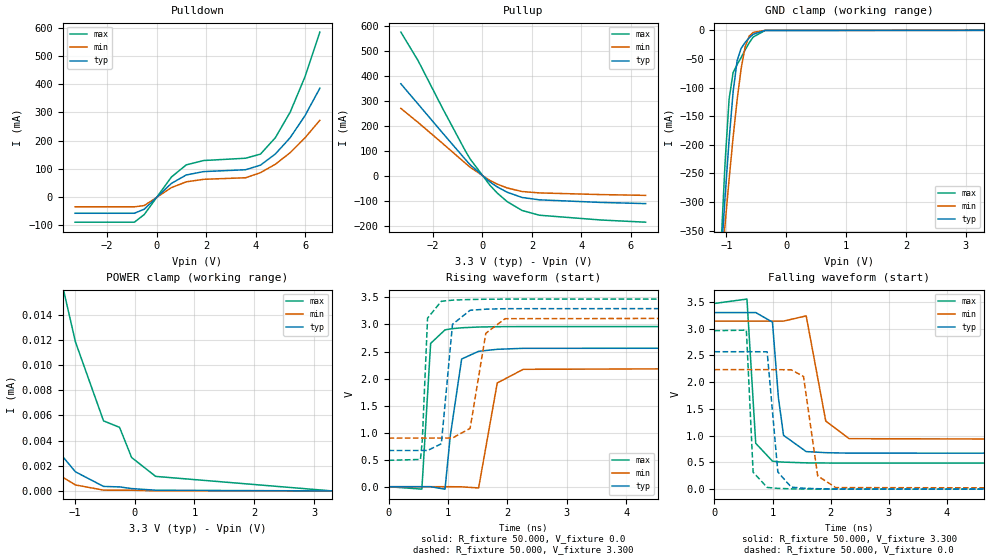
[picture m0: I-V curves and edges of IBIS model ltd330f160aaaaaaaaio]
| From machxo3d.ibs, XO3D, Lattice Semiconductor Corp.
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|   Model ltd330f160aaaaaaaaio
[Model] ltd330f160aaaaaaaaio
Model_type I/O
Polarity   Non-Inverting
Enable   Active-Low
Vinl =  0.800V
Vinh =  2.000V
Vmeas =  1.650V
Cref =  0.0F
Rref =  1.000M
Vref =  0.0V
C_comp   4.200pF   3.800pF   7.500pF
[Temperature Range]   25.000   0.105k   -40.000
[Voltage Range]   3.300V   3.140V   3.470V
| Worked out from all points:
|   slope of the pulldown table from 0 to 0.495 V, typ, clamps not added: 12.2 ohm
|   slope of the pullup table from 0 to 0.495 V, typ, clamps not added: 13.4 ohm
|   GND clamp passes 1 mA (typ) near -0.43 V on its own axis
|   rising waveform, R_fixture 50.000, V_fixture 0.0: 20-80 % time 126ps typ, 189ps min, 73.3ps max; typ from 0 V to 2.57 V
|   rising waveform, R_fixture 50.000, V_fixture 3.300: 20-80 % time 111ps typ, 191ps min, 60.7ps max; typ from 0.669 V to 3.3 V
|   falling waveform, R_fixture 50.000, V_fixture 3.300: 20-80 % time 131ps typ, 199ps min, 84.3ps max; typ from 3.3 V to 0.669 V
|   falling waveform, R_fixture 50.000, V_fixture 0.0: 20-80 % time 91ps typ, 147ps min, 59.8ps max; typ from 2.57 V to 0 V
[Pulldown]
|Voltage   I(typ)   I(min)   I(max)
-3.3V     -58.64mA   -35.81mA   -90.41mA
-900mV    -58.64mA   -35.81mA   -90.41mA
-500mV    -44.08mA   -31.23mA   -63.19mA
600mV     47.81mA    32.63mA    70.46mA
1.2V      77.59mA    53.08mA    113.6mA
1.9V      89.57mA    62.1mA     128.9mA
3.6V      96.17mA    67.69mA    137.1mA
4.2V      112.5mA    85.73mA    151.8mA
4.8V      152.1mA    115.6mA    210mA
5.4V      210.1mA    156.8mA    300.9mA
6V        288.6mA    209.7mA    426.9mA
6.6V      386.1mA    272mA      585.7mA
[Pullup]
|Voltage   I(typ)   I(min)   I(max)
-3.3V     369.2mA    270.7mA    576.2mA
-2.6V     287.7mA    214.3mA    461.4mA
-1.6V     171mA      129.5mA    268.6mA
-700mV    67.54mA    52.19mA    102.1mA
-500mV    45.33mA    35.19mA    68.56mA
300mV     -23.64mA   -17.66mA   -36.76mA
600mV     -43.66mA   -32.42mA   -68.28mA
1V        -64.93mA   -47.78mA   -102.5mA
1.6V      -85.8mA    -62.05mA   -137.8mA
2.3V      -95.32mA   -67.58mA   -156.9mA
4.8V      -105.7mA   -74.31mA   -176.1mA
6.6V      -110.4mA   -77.4mA    -184.8mA
[GND_clamp]
|Voltage   I(typ)   I(min)   I(max)
-3.3V     -4.507A    -3.482A    -6.263A
-1.089V   -398.4mA   -420.6mA   -374.7mA
-1.022V   -290.7mA   -338.6mA   -230.6mA
-955mV    -191.4mA   -260.2mA   -120.1mA
-888mV    -107.5mA   -187mA     -73.69mA
-821mV    -53mA      -121.4mA   -59.83mA
-754mV    -31.41mA   -66.95mA   -47.44mA
-687mV    -21.17mA   -28.83mA   -34.23mA
-620mV    -13.21mA   -10.24mA   -21.98mA
-553mV    -6.877mA   -3.592mA   -11.71mA
-352mV    -122.8uA   -54.62uA   -209.3uA
3.3V      0A         0A         0A
[POWER_clamp]
|Voltage   I(typ)   I(min)   I(max)
-3.3V     530uA      347.3uA    956.2uA
-2.663V   63.57uA    15.44uA    254.2uA
-2.529V   27.42uA    10.98uA    148.7uA
-2.328V   15.78uA    8.532uA    64.82uA
-1.725V   7.398uA    3.713uA    31uA
-1.189V   2.659uA    1.053uA    15.99uA
-988mV    1.516uA    474.5nA    11.83uA
-519mV    357.5nA    63.28nA    5.567uA
-251mV    319nA      55.54nA    5.047uA
-50mV     187.6nA    55.54nA    2.655uA
352mV     56.19nA    7.349nA    1.154uA
3.3V      0A         0A         0A
[Ramp]
| variable   typ   min   max
dV/dt_r   1.541/0.126n   1.340/0.188n   1.777/73.299p
dV/dt_f   1.578/0.131n   1.345/0.199n   1.790/84.112p
R_load = 50.000
[Rising Waveform]
R_fixture= 50.000
V_fixture= 0.0
V_fixture_min= 0.0
V_fixture_max= 0.0
|time   V(typ)   V(min)   V(max)
0s        9.963nV    27.08nV    122nV
560ps     34.49uV    15.04uV    -44.92mV
708ps     -6.996uV   15.04uV    2.651V
950ps     -45.42mV   101.8uV    2.9V
1.038ns   933.1mV    125.9uV    2.918V
1.23ns    2.361V     -2.495mV   2.939V
1.516ns   2.504V     -22.67mV   2.953V
1.83ns    2.541V     1.919V     2.959V
2.268ns   2.559V     2.171V     2.961V
20ns      2.568V     2.233V     2.961V
[Rising Waveform]
R_fixture= 50.000
V_fixture= 3.300
V_fixture_min= 3.140
V_fixture_max= 3.470
|time   V(typ)   V(min)   V(max)
0s        669.4mV    899.2mV    487.7mV
537ps     669.4mV    899.2mV    504.5mV
568ps     669.4mV    899.2mV    871mV
656ps     669.8mV    899.2mV    3.117V
888ps     794.2mV    899.2mV    3.429V
1.076ns   3.003V     900mV      3.45V
1.373ns   3.263V     1.08V      3.462V
1.637ns   3.283V     2.837V     3.467V
1.962ns   3.292V     3.107V     3.469V
20ns      3.3V       3.14V      3.47V
[Falling Waveform]
R_fixture= 50.000
V_fixture= 3.300
V_fixture_min= 3.140
V_fixture_max= 3.470
|time   V(typ)   V(min)   V(max)
0s        3.3V       3.14V      3.47V
560ps     3.3V       3.14V      3.552V
711ps     3.3V       3.14V      856.5mV
999ps     3.121V     3.14V      523.7mV
1.102ns   1.705V     3.14V      511.2mV
1.19ns    1.006V     3.14V      505.3mV
1.58ns    702.2mV    3.238V     491.4mV
1.917ns   681.9mV    1.273V     488.5mV
2.319ns   672.9mV    943.3mV    487.7mV
20ns      669.3mV    899.1mV    487.4mV
[Falling Waveform]
R_fixture= 50.000
V_fixture= 0.0
V_fixture_min= 0.0
V_fixture_max= 0.0
|time   V(typ)   V(min)   V(max)
0s        2.568V     2.233V     2.961V
550ps     2.568V     2.233V     2.971V
666ps     2.568V     2.233V     317.7mV
908ps     2.567V     2.233V     32.24mV
1.092ns   320.5mV    2.232V     14.99mV
1.322ns   38.14mV    2.231V     5.93mV
1.534ns   18.38mV    2.106V     2.77mV
1.778ns   8.352mV    247.8mV    1.035mV
2.089ns   3.24mV     29.24mV    364.9uV
20ns      -112.8nV   -14.59nV   18.02nV
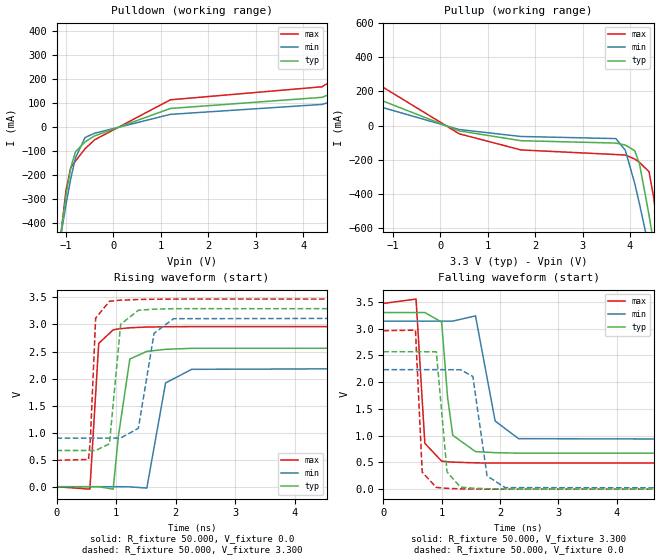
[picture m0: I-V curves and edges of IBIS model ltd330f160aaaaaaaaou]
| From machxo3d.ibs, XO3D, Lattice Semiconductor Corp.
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|   Model ltd330f160aaaaaaaaou
[Model] ltd330f160aaaaaaaaou
Model_type Output
Polarity   Non-Inverting
Enable   Active-High
Vmeas =  1.650V
Cref =  0.0F
Rref =  1.000M
Vref =  0.0V
C_comp   4.200pF   3.800pF   7.500pF
[Temperature Range]   25.000   0.105k   -40.000
[Voltage Range]   3.300V   3.140V   3.470V
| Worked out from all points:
|   slope of the pulldown table from 0 to 0.495 V, typ, clamps not added: 12.2 ohm
|   slope of the pullup table from 0 to 0.495 V, typ, clamps not added: 13.4 ohm
|   rising waveform, R_fixture 50.000, V_fixture 0.0: 20-80 % time 126ps typ, 188ps min, 73.3ps max; typ from 0 V to 2.57 V
|   rising waveform, R_fixture 50.000, V_fixture 3.300: 20-80 % time 111ps typ, 191ps min, 60.7ps max; typ from 0.669 V to 3.3 V
|   falling waveform, R_fixture 50.000, V_fixture 3.300: 20-80 % time 131ps typ, 199ps min, 84.3ps max; typ from 3.3 V to 0.669 V
|   falling waveform, R_fixture 50.000, V_fixture 0.0: 20-80 % time 91ps typ, 147ps min, 59.8ps max; typ from 2.57 V to 0 V
[Pulldown]
|Voltage   I(typ)   I(min)   I(max)
-3.3V     -4.508A    -3.483A    -6.264A
-1.1V     -430mA     -440.6mA   -433.4mA
-1V       -282.5mA   -321.4mA   -261.3mA
-900mV    -168.1mA   -213.9mA   -168.3mA
-800mV    -102.2mA   -127.5mA   -140.7mA
-600mV    -61.61mA   -43.3mA    -90.2mA
-400mV    -36.61mA   -25.5mA    -52.98mA
1.2V      77.59mA    53.08mA    113.6mA
4.4V      123.9mA    94.46mA    167.8mA
5.2V      188.6mA    141.7mA    266.7mA
6V        288.7mA    209.8mA    427mA
6.6V      386.7mA    272.5mA    586.4mA
[Pullup]
|Voltage   I(typ)   I(min)   I(max)
-3.3V     369.7mA    271mA      577.1mA
400mV     -30.71mA   -22.9mA    -47.84mA
1.7V      -88.05mA   -63.45mA   -141.9mA
3.7V      -101.9mA   -75.69mA   -168.8mA
3.9V      -113.4mA   -143.5mA   -171.5mA
4.1V      -146.7mA   -338.6mA   -195.2mA
4.2V      -224.4mA   -457.7mA   -214.8mA
4.4V      -521mA     -713.3mA   -268.6mA
4.5V      -691.6mA   -845.9mA   -420.8mA
4.6V      -867.9mA   -980.3mA   -645.1mA
4.7V      -1.048A    -1.116A    -890.7mA
6.6V      -4.617A    -3.787A    -5.985A
[Ramp]
| variable   typ   min   max
dV/dt_r   1.541/0.126n   1.340/0.188n   1.777/73.299p
dV/dt_f   1.578/0.131n   1.345/0.199n   1.790/84.112p
R_load = 50.000
[Rising Waveform]
R_fixture= 50.000
V_fixture= 0.0
V_fixture_min= 0.0
V_fixture_max= 0.0
|time   V(typ)   V(min)   V(max)
0s        9.963nV    27.08nV    122nV
560ps     34.49uV    15.09uV    -44.92mV
708ps     -6.995uV   15.09uV    2.651V
950ps     -45.42mV   101.8uV    2.9V
1.038ns   933.1mV    126uV      2.918V
1.23ns    2.361V     -2.495mV   2.939V
1.515ns   2.502V     -25.28mV   2.953V
1.83ns    2.541V     1.919V     2.958V
2.268ns   2.559V     2.171V     2.961V
20ns      2.568V     2.233V     2.961V
[Rising Waveform]
R_fixture= 50.000
V_fixture= 3.300
V_fixture_min= 3.140
V_fixture_max= 3.470
|time   V(typ)   V(min)   V(max)
0s        669.4mV    899.2mV    487.7mV
537ps     669.4mV    899.2mV    504.5mV
568ps     669.4mV    899.2mV    871mV
656ps     669.8mV    899.2mV    3.117V
888ps     794.2mV    899.2mV    3.429V
1.076ns   3.003V     900mV      3.45V
1.373ns   3.263V     1.08V      3.462V
1.637ns   3.283V     2.837V     3.467V
1.962ns   3.292V     3.107V     3.469V
20ns      3.3V       3.14V      3.47V
[Falling Waveform]
R_fixture= 50.000
V_fixture= 3.300
V_fixture_min= 3.140
V_fixture_max= 3.470
|time   V(typ)   V(min)   V(max)
0s        3.3V       3.14V      3.47V
560ps     3.3V       3.14V      3.552V
711ps     3.3V       3.14V      856.5mV
999ps     3.121V     3.14V      523.7mV
1.102ns   1.705V     3.14V      511.2mV
1.19ns    1.006V     3.14V      505.3mV
1.58ns    702.2mV    3.238V     491.4mV
1.917ns   681.9mV    1.273V     488.5mV
2.319ns   672.9mV    943.3mV    487.7mV
20ns      669.3mV    899.1mV    487.4mV
[Falling Waveform]
R_fixture= 50.000
V_fixture= 0.0
V_fixture_min= 0.0
V_fixture_max= 0.0
|time   V(typ)   V(min)   V(max)
0s        2.568V     2.233V     2.961V
550ps     2.568V     2.233V     2.971V
666ps     2.568V     2.233V     317.7mV
908ps     2.567V     2.233V     32.24mV
1.092ns   320.5mV    2.232V     14.99mV
1.322ns   38.14mV    2.231V     5.93mV
1.534ns   18.38mV    2.106V     2.77mV
1.778ns   8.352mV    247.8mV    1.035mV
2.089ns   3.24mV     29.24mV    364.9uV
20ns      -112.8nV   -14.59nV   18.02nV
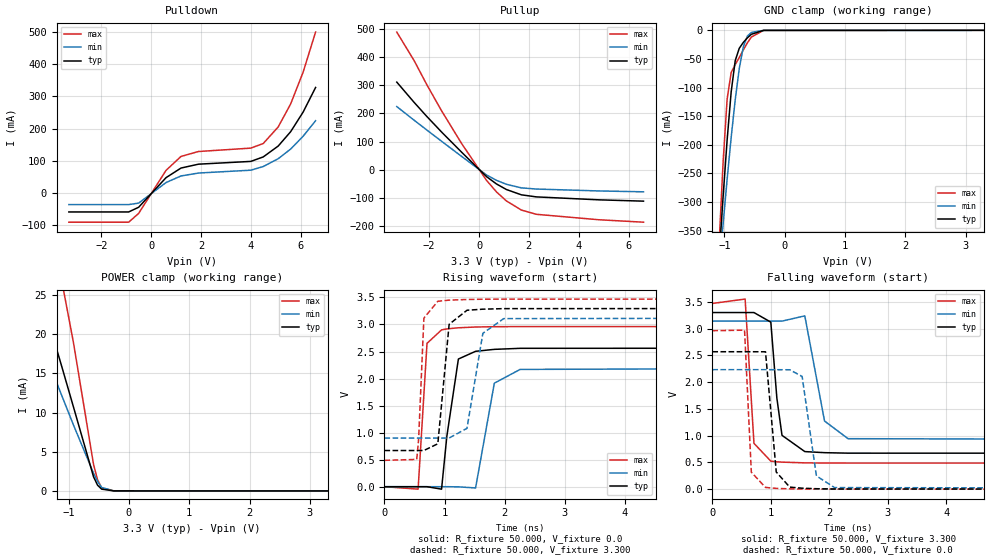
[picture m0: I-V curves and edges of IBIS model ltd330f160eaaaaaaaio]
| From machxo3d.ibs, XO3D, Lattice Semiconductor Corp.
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|   Model ltd330f160eaaaaaaaio
[Model] ltd330f160eaaaaaaaio
Model_type I/O
Polarity   Non-Inverting
Enable   Active-Low
Vinl =  0.800V
Vinh =  2.000V
Vmeas =  1.650V
Cref =  0.0F
Rref =  1.000M
Vref =  0.0V
C_comp   4.200pF   3.800pF   7.500pF
[Temperature Range]   25.000   0.105k   -40.000
[Voltage Range]   3.300V   3.140V   3.470V
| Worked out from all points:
|   slope of the pulldown table from 0 to 0.495 V, typ, clamps not added: 12.2 ohm
|   slope of the pullup table from 0 to 0.495 V, typ, clamps not added: 13.4 ohm
|   GND clamp passes 1 mA (typ) near -0.43 V on its own axis
|   POWER clamp passes 1 mA (typ) near -0.54 V on its own axis
|   rising waveform, R_fixture 50.000, V_fixture 0.0: 20-80 % time 126ps typ, 188ps min, 73.3ps max; typ from 0 V to 2.57 V
|   rising waveform, R_fixture 50.000, V_fixture 3.300: 20-80 % time 111ps typ, 191ps min, 60.7ps max; typ from 0.669 V to 3.3 V
|   falling waveform, R_fixture 50.000, V_fixture 3.300: 20-80 % time 131ps typ, 199ps min, 84.3ps max; typ from 3.3 V to 0.669 V
|   falling waveform, R_fixture 50.000, V_fixture 0.0: 20-80 % time 91ps typ, 147ps min, 59.8ps max; typ from 2.57 V to 0 V
[Pulldown]
|Voltage   I(typ)   I(min)   I(max)
-3.3V     -58.64mA   -35.81mA   -90.41mA
-900mV    -58.64mA   -35.81mA   -90.41mA
-500mV    -44.08mA   -31.23mA   -63.19mA
600mV     47.81mA    32.63mA    70.46mA
1.2V      77.59mA    53.08mA    113.6mA
1.9V      89.57mA    62.1mA     128.9mA
4V        98.2mA     70.91mA    139.4mA
4.5V      112.1mA    82.3mA     153.7mA
5.1V      145.8mA    106.5mA    205.1mA
5.6V      190.4mA    136.5mA    276.5mA
6.1V      251.2mA    176.2mA    375.1mA
6.6V      327.5mA    224.4mA    499.4mA
[Pullup]
|Voltage   I(typ)   I(min)   I(max)
-3.3V     310.5mA    224mA      487.4mA
-2.6V     238.5mA    175.5mA    386mA
-2.1V     189.6mA    141.5mA    302.2mA
-1.5V     133.8mA    101.2mA    208.7mA
-700mV    62.85mA    47.92mA    93.52mA
300mV     -23.64mA   -17.66mA   -36.76mA
700mV     -49.55mA   -36.72mA   -77.66mA
1.1V      -69.31mA   -50.87mA   -109.7mA
1.7V      -88.05mA   -63.45mA   -141.9mA
2.3V      -95.32mA   -67.58mA   -156.9mA
4.8V      -105.7mA   -74.31mA   -176.1mA
6.6V      -110.4mA   -77.4mA    -184.8mA
[GND_clamp]
|Voltage   I(typ)   I(min)   I(max)
-3.3V     -4.507A    -3.482A    -6.263A
-1.089V   -398.4mA   -420.6mA   -374.7mA
-1.022V   -290.7mA   -338.6mA   -230.6mA
-955mV    -191.4mA   -260.2mA   -120.1mA
-888mV    -107.5mA   -187mA     -73.69mA
-821mV    -53mA      -121.4mA   -59.83mA
-754mV    -31.41mA   -66.95mA   -47.44mA
-687mV    -21.17mA   -28.83mA   -34.23mA
-620mV    -13.21mA   -10.24mA   -21.98mA
-553mV    -6.877mA   -3.592mA   -11.71mA
-352mV    -122.8uA   -54.62uA   -209.3uA
3.3V      0A         0A         0A
[POWER_clamp]
|Voltage   I(typ)   I(min)   I(max)
-3.3V     59.07mA    46.89mA    89.53mA
-1.993V   37.2mA     28.86mA    58.21mA
-1.926V   35.72mA    27.66mA    56.06mA
-1.591V   27.94mA    21.43mA    44.69mA
-1.189V   17.87mA    13.66mA    29.79mA
-1.122V   16.12mA    12.35mA    27.17mA
-921mV    10.77mA    8.455mA    19.02mA
-586mV    1.798mA    2.256mA    3.367mA
-519mV    726.5uA    1.214mA    1.405mA
-452mV    229.1uA    443uA      409.2uA
-251mV    5.569uA    5.296uA    9.168uA
3.3V      0A         0A         0A
[Ramp]
| variable   typ   min   max
dV/dt_r   1.541/0.126n   1.340/0.188n   1.777/73.299p
dV/dt_f   1.578/0.131n   1.345/0.199n   1.790/84.112p
R_load = 50.000
[Rising Waveform]
R_fixture= 50.000
V_fixture= 0.0
V_fixture_min= 0.0
V_fixture_max= 0.0
|time   V(typ)   V(min)   V(max)
0s        9.963nV    27.08nV    122nV
560ps     34.48uV    15.05uV    -44.92mV
708ps     -6.981uV   15.05uV    2.651V
950ps     -45.42mV   101.8uV    2.9V
1.038ns   933.1mV    126uV      2.918V
1.23ns    2.361V     -2.495mV   2.939V
1.516ns   2.504V     -22.67mV   2.953V
1.828ns   2.54V      1.915V     2.959V
2.257ns   2.559V     2.169V     2.961V
20ns      2.568V     2.233V     2.961V
[Rising Waveform]
R_fixture= 50.000
V_fixture= 3.300
V_fixture_min= 3.140
V_fixture_max= 3.470
|time   V(typ)   V(min)   V(max)
0s        669.4mV    899.2mV    487.7mV
537ps     669.4mV    899.2mV    504.5mV
568ps     669.4mV    899.2mV    871mV
656ps     669.8mV    899.2mV    3.117V
888ps     794.2mV    899.2mV    3.429V
1.076ns   3.003V     900mV      3.45V
1.373ns   3.263V     1.08V      3.462V
1.637ns   3.283V     2.837V     3.467V
1.983ns   3.293V     3.108V     3.469V
20ns      3.3V       3.14V      3.47V
[Falling Waveform]
R_fixture= 50.000
V_fixture= 3.300
V_fixture_min= 3.140
V_fixture_max= 3.470
|time   V(typ)   V(min)   V(max)
0s        3.3V       3.14V      3.47V
560ps     3.3V       3.14V      3.552V
711ps     3.3V       3.14V      856.5mV
999ps     3.121V     3.14V      523.7mV
1.102ns   1.705V     3.14V      511.2mV
1.19ns    1.006V     3.14V      505.3mV
1.58ns    702.2mV    3.238V     491.4mV
1.917ns   681.9mV    1.273V     488.5mV
2.319ns   672.9mV    943.3mV    487.7mV
20ns      669.3mV    899.1mV    487.4mV
[Falling Waveform]
R_fixture= 50.000
V_fixture= 0.0
V_fixture_min= 0.0
V_fixture_max= 0.0
|time   V(typ)   V(min)   V(max)
0s        2.568V     2.233V     2.961V
550ps     2.568V     2.233V     2.971V
666ps     2.568V     2.233V     317.7mV
908ps     2.567V     2.233V     32.24mV
1.092ns   320.5mV    2.232V     14.99mV
1.322ns   38.14mV    2.231V     5.93mV
1.534ns   18.38mV    2.106V     2.77mV
1.778ns   8.352mV    247.8mV    1.035mV
2.089ns   3.24mV     29.24mV    364.9uV
20ns      -112.8nV   -14.59nV   18.02nV
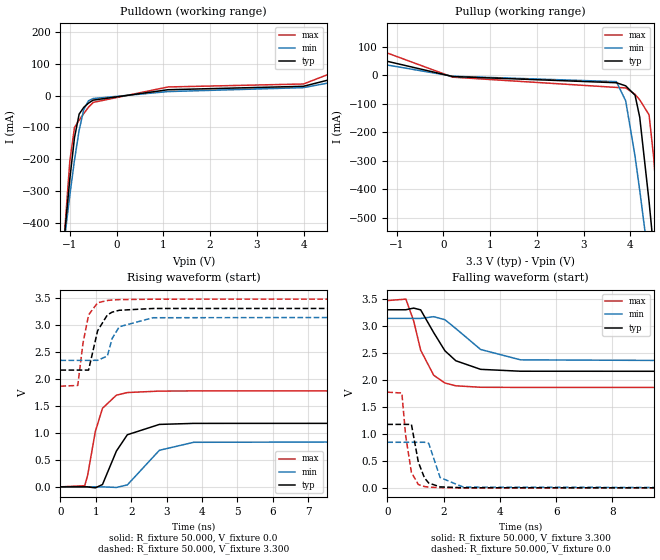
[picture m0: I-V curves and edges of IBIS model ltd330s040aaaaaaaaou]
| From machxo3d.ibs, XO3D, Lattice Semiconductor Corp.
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|   Model ltd330s040aaaaaaaaou
[Model] ltd330s040aaaaaaaaou
Model_type Output
Polarity   Non-Inverting
Enable   Active-High
Vmeas =  1.650V
Cref =  0.0F
Rref =  1.000M
Vref =  0.0V
C_comp   4.200pF   3.800pF   7.500pF
[Temperature Range]   25.000   0.105k   -40.000
[Voltage Range]   3.300V   3.140V   3.470V
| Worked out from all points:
|   slope of the pulldown table from 0 to 0.495 V, typ, clamps not added: 48.6 ohm
|   slope of the pullup table from 0 to 0.495 V, typ, clamps not added: 53.4 ohm
|   rising waveform, R_fixture 50.000, V_fixture 0.0: 20-80 % time 523ps typ, 706ps min, 357ps max; typ from 0 V to 1.18 V
|   rising waveform, R_fixture 50.000, V_fixture 3.300: 20-80 % time 307ps typ, 346ps min, 232ps max; typ from 2.16 V to 3.3 V
|   falling waveform, R_fixture 50.000, V_fixture 3.300: 20-80 % time 884ps typ, 1.22ns min, 622ps max; typ from 3.3 V to 2.16 V
|   falling waveform, R_fixture 50.000, V_fixture 0.0: 20-80 % time 310ps typ, 364ps min, 251ps max; typ from 1.18 V to 0 V
[Pulldown]
|Voltage   I(typ)   I(min)   I(max)
-3.3V     -4.507A    -3.482A    -6.263A
-1.1V     -420mA     -435.9mA   -408.3mA
-1V       -263.3mA   -314.6mA   -207.1mA
-900mV    -132.7mA   -203.2mA   -100.5mA
-800mV    -58.26mA   -109.1mA   -77.28mA
-700mV    -36.8mA    -43.36mA   -56.32mA
-600mV    -23.75mA   -16.45mA   -36.55mA
-500mV    -14.34mA   -9.257mA   -21.46mA
1.1V      18.49mA    12.63mA    27.15mA
4V        29.25mA    25.01mA    36.52mA
5.3V      77.78mA    61.08mA    110.5mA
6.6V      140.9mA    104mA      211.7mA
[Pullup]
|Voltage   I(typ)   I(min)   I(max)
-3.3V     100.8mA    70.9mA     162.3mA
-2.4V     95.01mA    70.07mA    150.9mA
200mV     -4.043mA   -3.026mA   -6.273mA
3.7V      -25.8mA    -21.94mA   -42.22mA
3.9V      -36.71mA   -89.31mA   -43.89mA
4.1V      -69.38mA   -284.1mA   -66.57mA
4.2V      -146.7mA   -403mA     -85.72mA
4.4V      -442.8mA   -658.2mA   -138.5mA
4.5V      -613.1mA   -790.6mA   -290.2mA
4.6V      -789.1mA   -924.9mA   -514mA
4.7V      -968.5mA   -1.061A    -759.2mA
6.6V      -4.534A    -3.729A    -5.846A
[Ramp]
| variable   typ   min   max
dV/dt_r   0.705/0.524n   0.507/0.711n   1.064/0.357n
dV/dt_f   0.685/0.885n   0.481/1.231n   0.965/0.627n
R_load = 50.000
[Rising Waveform]
R_fixture= 50.000
V_fixture= 0.0
V_fixture_min= 0.0
V_fixture_max= 0.0
|time   V(typ)   V(min)   V(max)
0s        26.18nV    63.38nV    354.7nV
686ps     532.1uV    -2.312uV   21.18mV
767ps     -1.056mV   -2.312uV   208.4mV
986ps     -18.76mV   90.44uV    1.023V
1.188ns   42.76mV    11.05uV    1.452V
1.582ns   662mV      -11.02mV   1.695V
1.89ns    962.8mV    35.51mV    1.743V
2.796ns   1.154V     675.6mV    1.77V
3.765ns   1.173V     823.5mV    1.773V
20ns      1.176V     844.4mV    1.773V
[Rising Waveform]
R_fixture= 50.000
V_fixture= 3.300
V_fixture_min= 3.140
V_fixture_max= 3.470
|time   V(typ)   V(min)   V(max)
0s        2.158V     2.338V     1.861V
489ps     2.158V     2.338V     1.874V
637ps     2.158V     2.338V     2.654V
795ps     2.158V     2.338V     3.178V
1.05ns    2.885V     2.339V     3.403V
1.326ns   3.178V     2.418V     3.445V
1.459ns   3.229V     2.74V      3.454V
1.662ns   3.264V     2.959V     3.461V
2.614ns   3.297V     3.126V     3.469V
20ns      3.3V       3.14V      3.47V
[Falling Waveform]
R_fixture= 50.000
V_fixture= 3.300
V_fixture_min= 3.140
V_fixture_max= 3.470
|time   V(typ)   V(min)   V(max)
0s        3.3V       3.14V      3.47V
659ps     3.3V       3.14V      3.497V
936ps     3.331V     3.14V      3.095V
1.185ns   3.298V     3.139V     2.551V
1.649ns   2.876V     3.172V     2.086V
2.047ns   2.54V      3.115V     1.943V
2.435ns   2.355V     2.952V     1.891V
3.316ns   2.196V     2.564V     1.864V
4.735ns   2.161V     2.372V     1.861V
20ns      2.158V     2.338V     1.861V
[Falling Waveform]
R_fixture= 50.000
V_fixture= 0.0
V_fixture_min= 0.0
V_fixture_max= 0.0
|time   V(typ)   V(min)   V(max)
0s        1.176V     844.4mV    1.773V
516ps     1.176V     844.4mV    1.757V
650ps     1.176V     844.4mV    973.6mV
856ps     1.176V     844.5mV    286mV
1.103ns   475.5mV    844.3mV    61.35mV
1.32ns    185.3mV    844.8mV    24.15mV
1.472ns   88.96mV    824.3mV    13.93mV
1.877ns   18.58mV    190.2mV    3.122mV
2.709ns   1.953mV    13.58mV    274uV
20ns      38.22nV    129.6nV    352.8nV
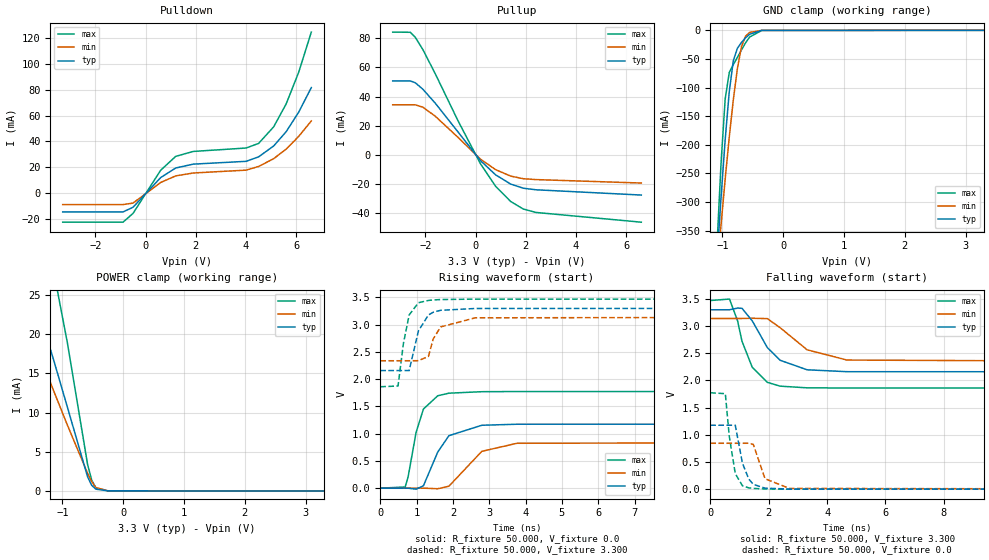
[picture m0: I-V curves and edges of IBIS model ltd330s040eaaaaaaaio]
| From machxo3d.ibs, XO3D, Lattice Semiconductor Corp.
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|   Model ltd330s040eaaaaaaaio
[Model] ltd330s040eaaaaaaaio
Model_type I/O
Polarity   Non-Inverting
Enable   Active-Low
Vinl =  0.800V
Vinh =  2.000V
Vmeas =  1.650V
Cref =  0.0F
Rref =  1.000M
Vref =  0.0V
C_comp   4.200pF   3.800pF   7.500pF
[Temperature Range]   25.000   0.105k   -40.000
[Voltage Range]   3.300V   3.140V   3.470V
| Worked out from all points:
|   slope of the pulldown table from 0 to 0.495 V, typ, clamps not added: 48.6 ohm
|   slope of the pullup table from 0 to 0.495 V, typ, clamps not added: 53.4 ohm
|   GND clamp passes 1 mA (typ) near -0.43 V on its own axis
|   POWER clamp passes 1 mA (typ) near -0.54 V on its own axis
|   rising waveform, R_fixture 50.000, V_fixture 0.0: 20-80 % time 523ps typ, 706ps min, 357ps max; typ from 0 V to 1.18 V
|   rising waveform, R_fixture 50.000, V_fixture 3.300: 20-80 % time 307ps typ, 346ps min, 232ps max; typ from 2.16 V to 3.3 V
|   falling waveform, R_fixture 50.000, V_fixture 3.300: 20-80 % time 877ps typ, 1.22ns min, 622ps max; typ from 3.3 V to 2.16 V
|   falling waveform, R_fixture 50.000, V_fixture 0.0: 20-80 % time 310ps typ, 365ps min, 251ps max; typ from 1.18 V to 0 V
[Pulldown]
|Voltage   I(typ)   I(min)   I(max)
-3.3V     -14.66mA   -8.951mA   -22.6mA
-900mV    -14.66mA   -8.951mA   -22.6mA
-500mV    -11.02mA   -7.807mA   -15.8mA
600mV     11.95mA    8.157mA    17.61mA
1.2V      19.4mA     13.27mA    28.41mA
1.9V      22.39mA    15.52mA    32.23mA
4V        24.55mA    17.73mA    34.86mA
4.5V      28.02mA    20.57mA    38.42mA
5.1V      36.45mA    26.6mA     51.27mA
5.6V      47.57mA    34.07mA    69.12mA
6.1V      62.73mA    43.93mA    93.72mA
6.6V      81.7mA     55.87mA    124.7mA
[Pullup]
|Voltage   I(typ)   I(min)   I(max)
-3.3V     50.71mA    34.32mA    84.22mA
-2.6V     50.71mA    34.32mA    84.08mA
-2.4V     49.45mA    34.32mA    80.61mA
-2.1V     45.03mA    32.7mA     72.26mA
-1.6V     35.33mA    26.42mA    55.44mA
-700mV    15.71mA    11.98mA    23.38mA
200mV     -4.043mA   -3.026mA   -6.275mA
800mV     -13.76mA   -10.18mA   -21.62mA
1.4V      -20.07mA   -14.6mA    -32.02mA
1.9V      -22.89mA   -16.38mA   -37.17mA
2.4V      -23.97mA   -16.98mA   -39.52mA
6.6V      -27.59mA   -19.35mA   -46.21mA
[GND_clamp]
|Voltage   I(typ)   I(min)   I(max)
-3.3V     -4.507A    -3.482A    -6.263A
-1.089V   -398.4mA   -420.6mA   -374.7mA
-1.022V   -290.7mA   -338.6mA   -230.6mA
-955mV    -191.4mA   -260.2mA   -120.1mA
-888mV    -107.5mA   -187mA     -73.69mA
-821mV    -53mA      -121.4mA   -59.83mA
-754mV    -31.41mA   -66.95mA   -47.44mA
-687mV    -21.17mA   -28.83mA   -34.23mA
-620mV    -13.21mA   -10.24mA   -21.98mA
-553mV    -6.877mA   -3.592mA   -11.71mA
-352mV    -122.8uA   -54.62uA   -209.3uA
3.3V      0A         0A         0A
[POWER_clamp]
|Voltage   I(typ)   I(min)   I(max)
-3.3V     59.07mA    46.89mA    89.53mA
-1.993V   37.2mA     28.86mA    58.21mA
-1.926V   35.72mA    27.66mA    56.06mA
-1.591V   27.94mA    21.43mA    44.69mA
-1.189V   17.87mA    13.66mA    29.79mA
-1.122V   16.12mA    12.35mA    27.17mA
-921mV    10.77mA    8.455mA    19.02mA
-586mV    1.798mA    2.256mA    3.367mA
-519mV    726.5uA    1.214mA    1.405mA
-452mV    229.1uA    443uA      409.2uA
-251mV    5.569uA    5.296uA    9.168uA
3.3V      0A         0A         0A
[Ramp]
| variable   typ   min   max
dV/dt_r   0.705/0.524n   0.507/0.711n   1.064/0.357n
dV/dt_f   0.685/0.885n   0.481/1.231n   0.965/0.627n
R_load = 50.000
[Rising Waveform]
R_fixture= 50.000
V_fixture= 0.0
V_fixture_min= 0.0
V_fixture_max= 0.0
|time   V(typ)   V(min)   V(max)
0s        26.18nV    63.38nV    354.7nV
686ps     532.1uV    -2.349uV   21.18mV
767ps     -1.056mV   -2.349uV   208.4mV
986ps     -18.76mV   90.45uV    1.023V
1.188ns   42.76mV    11.04uV    1.452V
1.582ns   662mV      -11.02mV   1.695V
1.89ns    962.8mV    35.51mV    1.743V
2.796ns   1.154V     675.6mV    1.77V
3.765ns   1.173V     823.5mV    1.773V
20ns      1.176V     844.4mV    1.773V
[Rising Waveform]
R_fixture= 50.000
V_fixture= 3.300
V_fixture_min= 3.140
V_fixture_max= 3.470
|time   V(typ)   V(min)   V(max)
0s        2.158V     2.338V     1.861V
489ps     2.158V     2.338V     1.874V
637ps     2.158V     2.338V     2.654V
795ps     2.158V     2.338V     3.178V
1.05ns    2.885V     2.339V     3.403V
1.326ns   3.178V     2.418V     3.445V
1.459ns   3.229V     2.74V      3.454V
1.662ns   3.264V     2.959V     3.461V
2.618ns   3.297V     3.126V     3.469V
20ns      3.3V       3.14V      3.47V
[Falling Waveform]
R_fixture= 50.000
V_fixture= 3.300
V_fixture_min= 3.140
V_fixture_max= 3.470
|time   V(typ)   V(min)   V(max)
0s        3.3V       3.14V      3.47V
659ps     3.3V       3.14V      3.497V
936ps     3.331V     3.14V      3.095V
1.085ns   3.327V     3.14V      2.723V
1.438ns   3.096V     3.144V     2.241V
1.956ns   2.603V     3.137V     1.965V
2.393ns   2.371V     2.97V      1.895V
3.316ns   2.196V     2.564V     1.864V
4.683ns   2.161V     2.375V     1.861V
20ns      2.158V     2.338V     1.861V
[Falling Waveform]
R_fixture= 50.000
V_fixture= 0.0
V_fixture_min= 0.0
V_fixture_max= 0.0
|time   V(typ)   V(min)   V(max)
0s        1.176V     844.4mV    1.773V
516ps     1.176V     844.3mV    1.757V
650ps     1.176V     844.3mV    973.6mV
856ps     1.176V     844.5mV    286mV
1.103ns   475.5mV    844.3mV    61.35mV
1.32ns    185.3mV    844.8mV    24.15mV
1.472ns   88.96mV    824.3mV    13.93mV
1.875ns   18.58mV    191.5mV    3.518mV
2.71ns    1.953mV    13.55mV    274uV
20ns      38.22nV    129.6nV    352.8nV
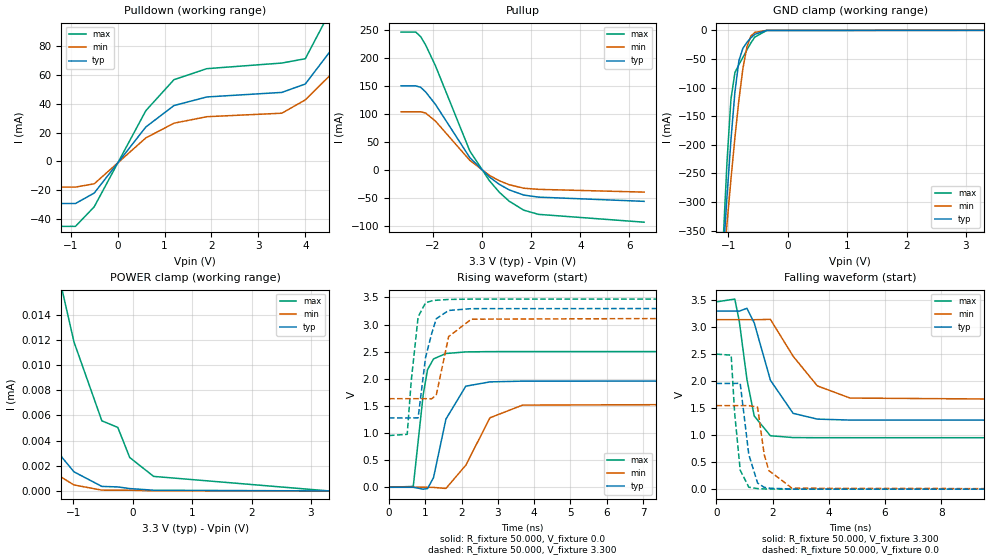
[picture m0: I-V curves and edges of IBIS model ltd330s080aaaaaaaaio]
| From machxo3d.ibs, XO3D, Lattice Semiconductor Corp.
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|   Model ltd330s080aaaaaaaaio
[Model] ltd330s080aaaaaaaaio
Model_type I/O
Polarity   Non-Inverting
Enable   Active-Low
Vinl =  0.800V
Vinh =  2.000V
Vmeas =  1.650V
Cref =  0.0F
Rref =  1.000M
Vref =  0.0V
C_comp   4.200pF   3.800pF   7.500pF
[Temperature Range]   25.000   0.105k   -40.000
[Voltage Range]   3.300V   3.140V   3.470V
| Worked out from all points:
|   slope of the pulldown table from 0 to 0.495 V, typ, clamps not added: 24.3 ohm
|   slope of the pullup table from 0 to 0.495 V, typ, clamps not added: 26.7 ohm
|   GND clamp passes 1 mA (typ) near -0.43 V on its own axis
|   rising waveform, R_fixture 50.000, V_fixture 0.0: 20-80 % time 416ps typ, 670ps min, 232ps max; typ from 0 V to 1.96 V
|   rising waveform, R_fixture 50.000, V_fixture 3.300: 20-80 % time 294ps typ, 337ps min, 207ps max; typ from 1.28 V to 3.3 V
|   falling waveform, R_fixture 50.000, V_fixture 3.300: 20-80 % time 774ps typ, 1.19ns min, 444ps max; typ from 3.3 V to 1.28 V
|   falling waveform, R_fixture 50.000, V_fixture 0.0: 20-80 % time 307ps typ, 355ps min, 231ps max; typ from 1.96 V to 0 V
[Pulldown]
|Voltage   I(typ)   I(min)   I(max)
-3.3V     -29.32mA   -17.9mA    -45.21mA
-900mV    -29.32mA   -17.9mA    -45.21mA
-500mV    -22.04mA   -15.61mA   -31.59mA
600mV     23.9mA     16.31mA    35.23mA
1.2V      38.8mA     26.54mA    56.81mA
1.9V      44.78mA    31.05mA    64.46mA
3.5V      47.95mA    33.48mA    68.37mA
4V        53.79mA    42.74mA    71.38mA
4.7V      83.76mA    65.33mA    114.8mA
5.3V      118.2mA    90.38mA    168.1mA
5.9V      161.6mA    120.5mA    237.1mA
6.6V      222.2mA    159.7mA    335.8mA
[Pullup]
|Voltage   I(typ)   I(min)   I(max)
-3.3V     151mA      104.7mA    247mA
-2.7V     151mA      104.7mA    247mA
-2.5V     148.4mA    104.7mA    238.8mA
-2.3V     140.2mA    102.5mA    224mA
-1.9V     118mA      88.17mA    187mA
-500mV    22.93mA    18.07mA    34.79mA
300mV     -11.82mA   -8.831mA   -18.38mA
700mV     -24.77mA   -18.36mA   -38.83mA
1.1V      -34.65mA   -25.44mA   -54.83mA
1.7V      -44.02mA   -31.73mA   -70.96mA
2.3V      -47.66mA   -33.79mA   -78.43mA
6.6V      -55.19mA   -38.7mA    -92.41mA
[GND_clamp]
|Voltage   I(typ)   I(min)   I(max)
-3.3V     -4.507A    -3.482A    -6.263A
-1.089V   -398.4mA   -420.6mA   -374.7mA
-1.022V   -290.7mA   -338.6mA   -230.6mA
-955mV    -191.4mA   -260.2mA   -120.1mA
-888mV    -107.5mA   -187mA     -73.69mA
-821mV    -53mA      -121.4mA   -59.83mA
-754mV    -31.41mA   -66.95mA   -47.44mA
-687mV    -21.17mA   -28.83mA   -34.23mA
-620mV    -13.21mA   -10.24mA   -21.98mA
-553mV    -6.877mA   -3.592mA   -11.71mA
-352mV    -122.8uA   -54.62uA   -209.3uA
3.3V      0A         0A         0A
[POWER_clamp]
|Voltage   I(typ)   I(min)   I(max)
-3.3V     530uA      347.3uA    956.2uA
-2.663V   63.57uA    15.44uA    254.2uA
-2.529V   27.42uA    10.98uA    148.7uA
-2.328V   15.78uA    8.532uA    64.82uA
-1.725V   7.398uA    3.714uA    31uA
-1.189V   2.659uA    1.053uA    15.99uA
-988mV    1.516uA    474.5nA    11.83uA
-519mV    357.5nA    63.32nA    5.567uA
-251mV    319nA      55.57nA    5.047uA
-50mV     187.6nA    55.57nA    2.655uA
352mV     56.19nA    7.349nA    1.154uA
3.3V      0A         0A         0A
[Ramp]
| variable   typ   min   max
dV/dt_r   1.175/0.417n   0.929/0.664n   1.501/0.231n
dV/dt_f   1.213/0.777n   0.904/1.189n   1.510/0.445n
R_load = 50.000
[Rising Waveform]
R_fixture= 50.000
V_fixture= 0.0
V_fixture_min= 0.0
V_fixture_max= 0.0
|time   V(typ)   V(min)   V(max)
0s        16.97nV    43.8nV     216.8nV
671ps     361.3uV    -4.473uV   15.92mV
945ps     -34.98mV   84.07uV    1.708V
1.064ns   -24.52mV   402.6uV    2.169V
1.229ns   177.8mV    -2.59mV    2.367V
1.571ns   1.257V     -21.89mV   2.466V
2.118ns   1.864V     406.7mV    2.496V
2.784ns   1.943V     1.281V     2.501V
3.682ns   1.957V     1.515V     2.502V
20ns      1.959V     1.548V     2.502V
[Rising Waveform]
R_fixture= 50.000
V_fixture= 3.300
V_fixture_min= 3.140
V_fixture_max= 3.470
|time   V(typ)   V(min)   V(max)
0s        1.278V     1.633V     953.3mV
504ps     1.278V     1.633V     975.9mV
613ps     1.278V     1.633V     1.946V
805ps     1.28V      1.633V     3.143V
1.01ns    2.395V     1.633V     3.402V
1.176ns   2.828V     1.632V     3.436V
1.304ns   3.107V     1.697V     3.448V
1.645ns   3.26V      2.777V     3.463V
2.268ns   3.293V     3.099V     3.469V
20ns      3.3V       3.14V      3.47V
[Falling Waveform]
R_fixture= 50.000
V_fixture= 3.300
V_fixture_min= 3.140
V_fixture_max= 3.470
|time   V(typ)   V(min)   V(max)
0s        3.3V       3.14V      3.47V
655ps     3.3V       3.14V      3.522V
814ps     3.298V     3.14V      3.115V
1.086ns   3.351V     3.14V      2.038V
1.347ns   3.08V      3.139V     1.355V
1.923ns   2.018V     3.146V     990mV
2.731ns   1.405V     2.463V     955.9mV
3.592ns   1.298V     1.914V     953.4mV
4.759ns   1.28V      1.688V     953.3mV
20ns      1.278V     1.633V     953.2mV
[Falling Waveform]
R_fixture= 50.000
V_fixture= 0.0
V_fixture_min= 0.0
V_fixture_max= 0.0
|time   V(typ)   V(min)   V(max)
0s        1.959V     1.548V     2.502V
526ps     1.959V     1.548V     2.483V
648ps     1.959V     1.548V     1.421V
847ps     1.962V     1.548V     353.3mV
1.154ns   639.8mV    1.548V     35.56mV
1.466ns   113.4mV    1.52V      10.67mV
1.701ns   33.98mV    640.2mV    4.22mV
1.868ns   18.49mV    344.4mV    2.291mV
2.694ns   1.878mV    17.36mV    235.4uV
20ns      27.08nV    115.5nV    216.8nV
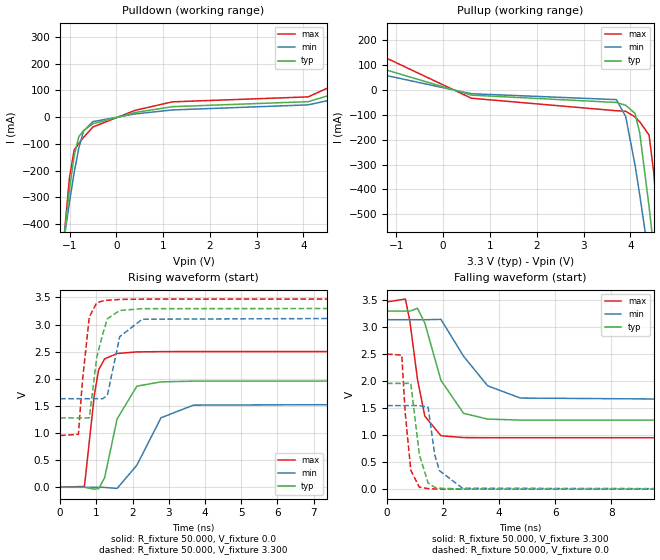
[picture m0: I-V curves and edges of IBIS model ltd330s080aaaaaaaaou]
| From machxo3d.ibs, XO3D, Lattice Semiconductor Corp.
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|   Model ltd330s080aaaaaaaaou
[Model] ltd330s080aaaaaaaaou
Model_type Output
Polarity   Non-Inverting
Enable   Active-High
Vmeas =  1.650V
Cref =  0.0F
Rref =  1.000M
Vref =  0.0V
C_comp   4.200pF   3.800pF   7.500pF
[Temperature Range]   25.000   0.105k   -40.000
[Voltage Range]   3.300V   3.140V   3.470V
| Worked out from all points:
|   slope of the pulldown table from 0 to 0.495 V, typ, clamps not added: 24.3 ohm
|   slope of the pullup table from 0 to 0.495 V, typ, clamps not added: 26.7 ohm
|   rising waveform, R_fixture 50.000, V_fixture 0.0: 20-80 % time 416ps typ, 670ps min, 232ps max; typ from 0 V to 1.96 V
|   rising waveform, R_fixture 50.000, V_fixture 3.300: 20-80 % time 294ps typ, 337ps min, 207ps max; typ from 1.28 V to 3.3 V
|   falling waveform, R_fixture 50.000, V_fixture 3.300: 20-80 % time 774ps typ, 1.19ns min, 444ps max; typ from 3.3 V to 1.28 V
|   falling waveform, R_fixture 50.000, V_fixture 0.0: 20-80 % time 307ps typ, 355ps min, 231ps max; typ from 1.96 V to 0 V
[Pulldown]
|Voltage   I(typ)   I(min)   I(max)
-3.3V     -4.507A    -3.482A    -6.263A
-1.1V     -423.4mA   -437.5mA   -416.7mA
-1V       -269.7mA   -316.9mA   -225.1mA
-900mV    -144.5mA   -206.8mA   -123.1mA
-800mV    -72.92mA   -115.2mA   -98.42mA
-700mV    -50.73mA   -52.06mA   -75.89mA
-500mV    -25.36mA   -17.06mA   -37.25mA
400mV     16.94mA    11.56mA    24.96mA
1.2V      38.8mA     26.54mA    56.81mA
4.1V      57.47mA    45.51mA    75.33mA
5.4V      124.8mA    95.07mA    178.5mA
6.6V      222.7mA    160.2mA    336.5mA
[Pullup]
|Voltage   I(typ)   I(min)   I(max)
-3.3V     151.1mA    104.7mA    247.2mA
-2.4V     144.7mA    104.5mA    232mA
600mV     -21.83mA   -16.21mA   -34.14mA
3.7V      -51.18mA   -39.85mA   -84.43mA
3.9V      -62.28mA   -107.4mA   -86.42mA
4.1V      -95.15mA   -302.3mA   -109.4mA
4.2V      -172.6mA   -421.2mA   -128.8mA
4.4V      -468.8mA   -676.6mA   -181.9mA
4.5V      -639.3mA   -809mA     -333.7mA
4.6V      -815.4mA   -943.4mA   -557.7mA
4.7V      -994.9mA   -1.079A    -803mA
6.6V      -4.562A    -3.748A    -5.893A
[Ramp]
| variable   typ   min   max
dV/dt_r   1.175/0.417n   0.929/0.664n   1.501/0.231n
dV/dt_f   1.213/0.777n   0.904/1.189n   1.510/0.445n
R_load = 50.000
[Rising Waveform]
R_fixture= 50.000
V_fixture= 0.0
V_fixture_min= 0.0
V_fixture_max= 0.0
|time   V(typ)   V(min)   V(max)
0s        16.97nV    43.8nV     216.8nV
671ps     361.3uV    -4.399uV   15.92mV
945ps     -34.98mV   84.06uV    1.708V
1.064ns   -24.52mV   402.6uV    2.169V
1.229ns   177.8mV    -2.59mV    2.367V
1.571ns   1.257V     -21.89mV   2.466V
2.118ns   1.864V     406.7mV    2.496V
2.784ns   1.943V     1.281V     2.501V
3.682ns   1.957V     1.515V     2.502V
20ns      1.959V     1.548V     2.502V
[Rising Waveform]
R_fixture= 50.000
V_fixture= 3.300
V_fixture_min= 3.140
V_fixture_max= 3.470
|time   V(typ)   V(min)   V(max)
0s        1.278V     1.633V     953.3mV
504ps     1.278V     1.633V     975.9mV
613ps     1.278V     1.633V     1.946V
805ps     1.28V      1.633V     3.143V
1.01ns    2.395V     1.633V     3.402V
1.176ns   2.828V     1.632V     3.436V
1.304ns   3.107V     1.697V     3.448V
1.645ns   3.26V      2.777V     3.463V
2.268ns   3.293V     3.099V     3.469V
20ns      3.3V       3.14V      3.47V
[Falling Waveform]
R_fixture= 50.000
V_fixture= 3.300
V_fixture_min= 3.140
V_fixture_max= 3.470
|time   V(typ)   V(min)   V(max)
0s        3.3V       3.14V      3.47V
655ps     3.3V       3.14V      3.522V
814ps     3.298V     3.14V      3.115V
1.086ns   3.351V     3.14V      2.038V
1.347ns   3.08V      3.139V     1.355V
1.923ns   2.018V     3.146V     990mV
2.731ns   1.405V     2.463V     955.9mV
3.592ns   1.298V     1.914V     953.4mV
4.759ns   1.28V      1.688V     953.3mV
20ns      1.278V     1.633V     953.2mV
[Falling Waveform]
R_fixture= 50.000
V_fixture= 0.0
V_fixture_min= 0.0
V_fixture_max= 0.0
|time   V(typ)   V(min)   V(max)
0s        1.959V     1.548V     2.502V
526ps     1.959V     1.548V     2.483V
648ps     1.959V     1.548V     1.421V
847ps     1.962V     1.548V     353.3mV
1.154ns   639.8mV    1.548V     35.56mV
1.466ns   113.4mV    1.52V      10.67mV
1.701ns   33.98mV    640.2mV    4.22mV
1.868ns   18.49mV    344.4mV    2.291mV
2.694ns   1.878mV    17.36mV    235.4uV
20ns      27.08nV    115.5nV    216.8nV
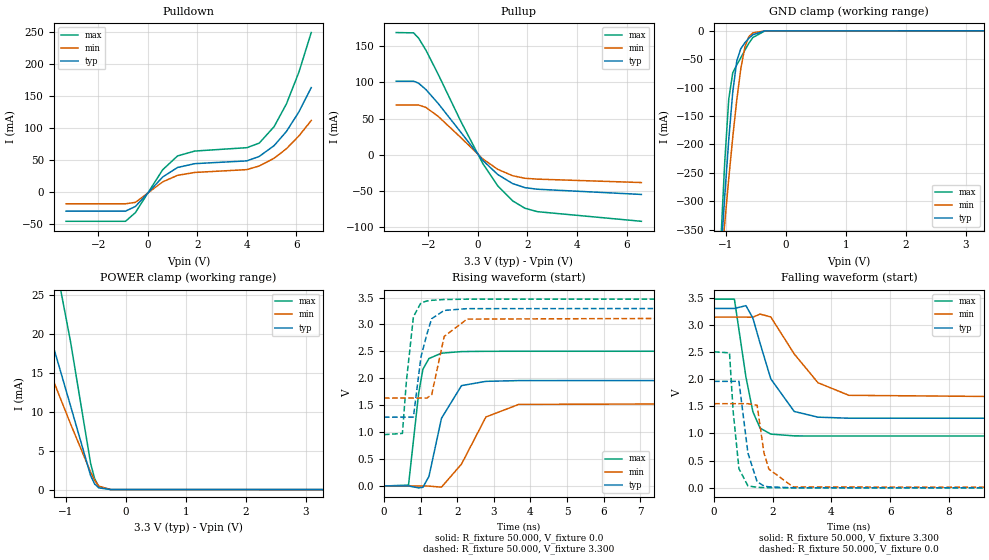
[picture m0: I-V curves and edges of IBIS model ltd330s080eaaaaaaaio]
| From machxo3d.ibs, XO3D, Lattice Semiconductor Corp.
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|   Model ltd330s080eaaaaaaaio
[Model] ltd330s080eaaaaaaaio
Model_type I/O
Polarity   Non-Inverting
Enable   Active-Low
Vinl =  0.800V
Vinh =  2.000V
Vmeas =  1.650V
Cref =  0.0F
Rref =  1.000M
Vref =  0.0V
C_comp   4.200pF   3.800pF   7.500pF
[Temperature Range]   25.000   0.105k   -40.000
[Voltage Range]   3.300V   3.140V   3.470V
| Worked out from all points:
|   slope of the pulldown table from 0 to 0.495 V, typ, clamps not added: 24.3 ohm
|   slope of the pullup table from 0 to 0.495 V, typ, clamps not added: 26.7 ohm
|   GND clamp passes 1 mA (typ) near -0.43 V on its own axis
|   POWER clamp passes 1 mA (typ) near -0.54 V on its own axis
|   rising waveform, R_fixture 50.000, V_fixture 0.0: 20-80 % time 416ps typ, 670ps min, 232ps max; typ from 0 V to 1.96 V
|   rising waveform, R_fixture 50.000, V_fixture 3.300: 20-80 % time 294ps typ, 337ps min, 207ps max; typ from 1.28 V to 3.3 V
|   falling waveform, R_fixture 50.000, V_fixture 3.300: 20-80 % time 781ps typ, 1.19ns min, 444ps max; typ from 3.3 V to 1.28 V
|   falling waveform, R_fixture 50.000, V_fixture 0.0: 20-80 % time 307ps typ, 355ps min, 231ps max; typ from 1.96 V to 0 V
[Pulldown]
|Voltage   I(typ)   I(min)   I(max)
-3.3V     -29.32mA   -17.9mA    -45.21mA
-900mV    -29.32mA   -17.9mA    -45.21mA
-500mV    -22.04mA   -15.61mA   -31.59mA
600mV     23.9mA     16.31mA    35.23mA
1.2V      38.8mA     26.54mA    56.81mA
1.9V      44.78mA    31.05mA    64.46mA
4V        49.1mA     35.45mA    69.72mA
4.5V      56.03mA    41.14mA    76.83mA
5.1V      72.88mA    53.19mA    102.5mA
5.6V      95.14mA    68.16mA    138.2mA
6.1V      125.5mA    87.96mA    187.4mA
6.6V      163.5mA    112.1mA    249.4mA
[Pullup]
|Voltage   I(typ)   I(min)   I(max)
-3.3V     101.8mA    68.78mA    169.2mA
-2.6V     101.8mA    68.78mA    168.8mA
-2.4V     99.13mA    68.78mA    161.7mA
-2.1V     90.21mA    65.46mA    144.8mA
-1.6V     70.71mA    52.86mA    111mA
-700mV    31.42mA    23.96mA    46.76mA
200mV     -8.086mA   -6.051mA   -12.55mA
800mV     -27.53mA   -20.35mA   -43.24mA
1.4V      -40.13mA   -29.21mA   -64.05mA
1.9V      -45.78mA   -32.75mA   -74.34mA
2.4V      -47.95mA   -33.97mA   -79.05mA
6.6V      -55.19mA   -38.7mA    -92.41mA
[GND_clamp]
|Voltage   I(typ)   I(min)   I(max)
-3.3V     -4.507A    -3.482A    -6.263A
-1.089V   -398.4mA   -420.6mA   -374.7mA
-1.022V   -290.7mA   -338.6mA   -230.6mA
-955mV    -191.4mA   -260.2mA   -120.1mA
-888mV    -107.5mA   -187mA     -73.69mA
-821mV    -53mA      -121.4mA   -59.83mA
-754mV    -31.41mA   -66.95mA   -47.44mA
-687mV    -21.17mA   -28.83mA   -34.23mA
-620mV    -13.21mA   -10.24mA   -21.98mA
-553mV    -6.877mA   -3.592mA   -11.71mA
-352mV    -122.8uA   -54.62uA   -209.3uA
3.3V      0A         0A         0A
[POWER_clamp]
|Voltage   I(typ)   I(min)   I(max)
-3.3V     59.07mA    46.89mA    89.53mA
-1.993V   37.2mA     28.86mA    58.21mA
-1.926V   35.72mA    27.66mA    56.06mA
-1.591V   27.94mA    21.43mA    44.69mA
-1.189V   17.87mA    13.66mA    29.79mA
-1.122V   16.12mA    12.35mA    27.17mA
-921mV    10.77mA    8.455mA    19.02mA
-586mV    1.798mA    2.256mA    3.367mA
-519mV    726.5uA    1.214mA    1.405mA
-452mV    229.1uA    443uA      409.2uA
-251mV    5.569uA    5.296uA    9.168uA
3.3V      0A         0A         0A
[Ramp]
| variable   typ   min   max
dV/dt_r   1.175/0.417n   0.929/0.664n   1.501/0.231n
dV/dt_f   1.213/0.777n   0.904/1.189n   1.510/0.445n
R_load = 50.000
[Rising Waveform]
R_fixture= 50.000
V_fixture= 0.0
V_fixture_min= 0.0
V_fixture_max= 0.0
|time   V(typ)   V(min)   V(max)
0s        16.97nV    43.8nV     216.8nV
671ps     361.3uV    -4.474uV   15.92mV
945ps     -34.98mV   84.07uV    1.708V
1.064ns   -24.52mV   402.6uV    2.169V
1.229ns   177.8mV    -2.59mV    2.367V
1.571ns   1.257V     -21.89mV   2.466V
2.118ns   1.864V     406.7mV    2.496V
2.784ns   1.943V     1.281V     2.501V
3.682ns   1.957V     1.515V     2.502V
20ns      1.959V     1.548V     2.502V
[Rising Waveform]
R_fixture= 50.000
V_fixture= 3.300
V_fixture_min= 3.140
V_fixture_max= 3.470
|time   V(typ)   V(min)   V(max)
0s        1.278V     1.633V     953.3mV
504ps     1.278V     1.633V     975.9mV
613ps     1.278V     1.633V     1.946V
805ps     1.28V      1.633V     3.143V
1.01ns    2.395V     1.633V     3.402V
1.176ns   2.828V     1.632V     3.436V
1.304ns   3.107V     1.697V     3.448V
1.645ns   3.26V      2.777V     3.463V
2.268ns   3.293V     3.099V     3.469V
20ns      3.3V       3.14V      3.47V
[Falling Waveform]
R_fixture= 50.000
V_fixture= 3.300
V_fixture_min= 3.140
V_fixture_max= 3.470
|time   V(typ)   V(min)   V(max)
0s        3.3V       3.14V      3.47V
693ps     3.299V     3.14V      3.471V
1.086ns   3.351V     3.14V      2.038V
1.323ns   3.121V     3.139V     1.4V
1.567ns   2.66V      3.196V     1.099V
1.933ns   2.004V     3.143V     988.7mV
2.731ns   1.405V     2.463V     955.9mV
3.542ns   1.3V       1.933V     953.6mV
4.595ns   1.281V     1.702V     953.3mV
20ns      1.278V     1.633V     953.2mV
[Falling Waveform]
R_fixture= 50.000
V_fixture= 0.0
V_fixture_min= 0.0
V_fixture_max= 0.0
|time   V(typ)   V(min)   V(max)
0s        1.959V     1.548V     2.502V
526ps     1.959V     1.548V     2.483V
648ps     1.959V     1.548V     1.421V
847ps     1.962V     1.548V     353.3mV
1.154ns   639.8mV    1.548V     35.56mV
1.466ns   113.4mV    1.52V      10.67mV
1.701ns   33.98mV    640.2mV    4.22mV
1.868ns   18.49mV    344.4mV    2.291mV
2.694ns   1.878mV    17.36mV    235.4uV
20ns      27.08nV    115.5nV    216.8nV
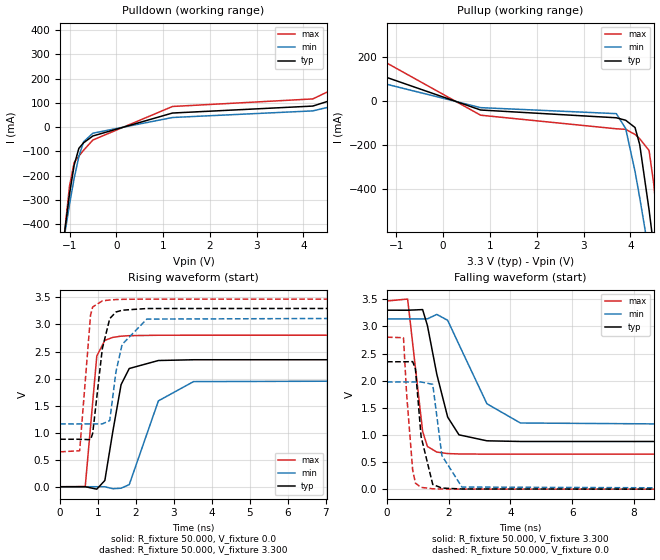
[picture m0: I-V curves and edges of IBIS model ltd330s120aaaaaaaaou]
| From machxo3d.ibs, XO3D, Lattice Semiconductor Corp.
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|   Model ltd330s120aaaaaaaaou
[Model] ltd330s120aaaaaaaaou
Model_type Output
Polarity   Non-Inverting
Enable   Active-High
Vmeas =  1.650V
Cref =  0.0F
Rref =  1.000M
Vref =  0.0V
C_comp   4.200pF   3.800pF   7.500pF
[Temperature Range]   25.000   0.105k   -40.000
[Voltage Range]   3.300V   3.140V   3.470V
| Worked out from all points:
|   slope of the pulldown table from 0 to 0.495 V, typ, clamps not added: 16.2 ohm
|   slope of the pullup table from 0 to 0.495 V, typ, clamps not added: 17.8 ohm
|   rising waveform, R_fixture 50.000, V_fixture 0.0: 20-80 % time 328ps typ, 552ps min, 175ps max; typ from 0 V to 2.35 V
|   rising waveform, R_fixture 50.000, V_fixture 3.300: 20-80 % time 287ps typ, 332ps min, 189ps max; typ from 0.878 V to 3.3 V
|   falling waveform, R_fixture 50.000, V_fixture 3.300: 20-80 % time 563ps typ, 986ps min, 306ps max; typ from 3.3 V to 0.878 V
|   falling waveform, R_fixture 50.000, V_fixture 0.0: 20-80 % time 295ps typ, 350ps min, 206ps max; typ from 2.35 V to 0 V
[Pulldown]
|Voltage   I(typ)   I(min)   I(max)
-3.3V     -4.507A    -3.483A    -6.263A
-1.1V     -426.7mA   -439mA     -425mA
-1V       -276.1mA   -319.1mA   -243.2mA
-900mV    -156.3mA   -210.3mA   -145.7mA
-800mV    -87.58mA   -121.4mA   -119.6mA
-700mV    -64.66mA   -60.75mA   -95.46mA
-500mV    -36.38mA   -24.87mA   -53.05mA
1.2V      58.2mA     39.81mA    85.22mA
4.2V      86.95mA    67.09mA    116.4mA
5.1V      142.2mA    108.1mA    199.8mA
6.4V      278.1mA    199.6mA    418.1mA
6.6V      304.4mA    216.1mA    461.1mA
[Pullup]
|Voltage   I(typ)   I(min)   I(max)
-3.3V     202.4mA    139.1mA    333.1mA
-2.4V     194.7mA    139.1mA    313.5mA
800mV     -41.29mA   -30.53mA   -64.86mA
3.7V      -76.56mA   -57.77mA   -126.6mA
3.9V      -87.85mA   -125.4mA   -129mA
4.1V      -120.9mA   -320.5mA   -152.3mA
4.2V      -198.5mA   -439.5mA   -171.8mA
4.4V      -494.9mA   -694.9mA   -225.2mA
4.5V      -665.5mA   -827.4mA   -377.2mA
4.6V      -841.6mA   -961.9mA   -601.4mA
4.7V      -1.021A    -1.098A    -846.9mA
6.6V      -4.589A    -3.768A    -5.939A
[Ramp]
| variable   typ   min   max
dV/dt_r   1.409/0.327n   1.186/0.554n   1.681/0.175n
dV/dt_f   1.453/0.564n   1.187/0.981n   1.695/0.307n
R_load = 50.000
[Rising Waveform]
R_fixture= 50.000
V_fixture= 0.0
V_fixture_min= 0.0
V_fixture_max= 0.0
|time   V(typ)   V(min)   V(max)
0s        12.56nV    33.46nV    156.1nV
661ps     270.8uV    -6.325uV   3.891mV
966ps     -44.88mV   131.8uV    2.418V
1.178ns   116.3mV    -129.2uV   2.706V
1.39ns    1.029V     -36.65mV   2.762V
1.606ns   1.888V     -27.29mV   2.784V
1.821ns   2.186V     39.12mV    2.793V
2.59ns    2.334V     1.588V     2.801V
3.515ns   2.348V     1.944V     2.802V
20ns      2.349V     1.976V     2.802V
[Rising Waveform]
R_fixture= 50.000
V_fixture= 3.300
V_fixture_min= 3.140
V_fixture_max= 3.470
|time   V(typ)   V(min)   V(max)
0s        878.1mV    1.161V     645.8mV
514ps     878.1mV    1.161V     665.1mV
802ps     870mV      1.161V     3.177V
858ps     989.1mV    1.161V     3.324V
1.111ns   2.552V     1.162V     3.436V
1.307ns   3.108V     1.222V     3.454V
1.469ns   3.23V      2.119V     3.461V
1.633ns   3.264V     2.631V     3.465V
2.285ns   3.295V     3.1V       3.469V
20ns      3.3V       3.14V      3.47V
[Falling Waveform]
R_fixture= 50.000
V_fixture= 3.300
V_fixture_min= 3.140
V_fixture_max= 3.470
|time   V(typ)   V(min)   V(max)
0s        3.3V       3.14V      3.47V
668ps     3.299V     3.14V      3.505V
1.153ns   3.311V     3.139V     1.067V
1.308ns   3.019V     3.14V      787.7mV
1.613ns   2.118V     3.222V     683.9mV
1.965ns   1.329V     3.113V     656.4mV
2.331ns   1.002V     2.667V     648.9mV
3.236ns   891.5mV    1.575V     646mV
4.321ns   879.4mV    1.22V      645.8mV
20ns      878mV      1.161V     645.8mV
[Falling Waveform]
R_fixture= 50.000
V_fixture= 0.0
V_fixture_min= 0.0
V_fixture_max= 0.0
|time   V(typ)   V(min)   V(max)
0s        2.349V     1.976V     2.802V
533ps     2.349V     1.976V     2.792V
635ps     2.349V     1.976V     1.755V
830ps     2.352V     1.976V     356.1mV
920ps     2.219V     1.976V     111.2mV
1.104ns   968.8mV    1.976V     32.74mV
1.481ns   86.75mV    1.933V     7.27mV
1.778ns   20.62mV    619.7mV    2.553mV
2.427ns   3.086mV    39.1mV     303.4uV
20ns      19.28nV    99.97nV    155nV
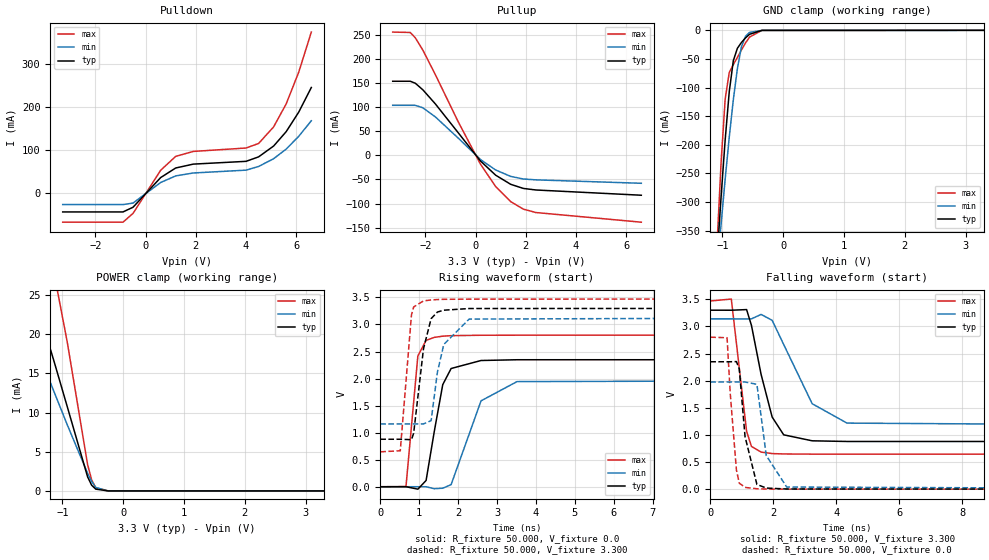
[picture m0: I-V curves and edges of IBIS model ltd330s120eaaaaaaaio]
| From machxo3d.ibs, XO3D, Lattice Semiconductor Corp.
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|   Model ltd330s120eaaaaaaaio
[Model] ltd330s120eaaaaaaaio
Model_type I/O
Polarity   Non-Inverting
Enable   Active-Low
Vinl =  0.800V
Vinh =  2.000V
Vmeas =  1.650V
Cref =  0.0F
Rref =  1.000M
Vref =  0.0V
C_comp   4.200pF   3.800pF   7.500pF
[Temperature Range]   25.000   0.105k   -40.000
[Voltage Range]   3.300V   3.140V   3.470V
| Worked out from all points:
|   slope of the pulldown table from 0 to 0.495 V, typ, clamps not added: 16.2 ohm
|   slope of the pullup table from 0 to 0.495 V, typ, clamps not added: 17.8 ohm
|   GND clamp passes 1 mA (typ) near -0.43 V on its own axis
|   POWER clamp passes 1 mA (typ) near -0.54 V on its own axis
|   rising waveform, R_fixture 50.000, V_fixture 0.0: 20-80 % time 328ps typ, 552ps min, 175ps max; typ from 0 V to 2.35 V
|   rising waveform, R_fixture 50.000, V_fixture 3.300: 20-80 % time 287ps typ, 332ps min, 189ps max; typ from 0.878 V to 3.3 V
|   falling waveform, R_fixture 50.000, V_fixture 3.300: 20-80 % time 563ps typ, 986ps min, 306ps max; typ from 3.3 V to 0.878 V
|   falling waveform, R_fixture 50.000, V_fixture 0.0: 20-80 % time 295ps typ, 350ps min, 206ps max; typ from 2.35 V to 0 V
[Pulldown]
|Voltage   I(typ)   I(min)   I(max)
-3.3V     -43.98mA   -26.85mA   -67.81mA
-900mV    -43.98mA   -26.85mA   -67.81mA
-500mV    -33.06mA   -23.42mA   -47.39mA
600mV     35.86mA    24.47mA    52.84mA
1.2V      58.2mA     39.81mA    85.22mA
1.9V      67.18mA    46.57mA    96.69mA
4V        73.65mA    53.18mA    104.6mA
4.5V      84.05mA    61.72mA    115.2mA
5.1V      109.3mA    79.79mA    153.8mA
5.6V      142.7mA    102.2mA    207.3mA
6.1V      188.2mA    131.9mA    281.1mA
6.6V      245.3mA    168mA      374.1mA
[Pullup]
|Voltage   I(typ)   I(min)   I(max)
-3.3V     153.2mA    103.4mA    255mA
-2.6V     153.2mA    103.4mA    254.2mA
-2.4V     149.1mA    103.4mA    243.2mA
-2.1V     135.5mA    98.29mA    217.7mA
-1.6V     106.2mA    79.33mA    166.7mA
-700mV    47.13mA    35.94mA    70.14mA
200mV     -12.13mA   -9.077mA   -18.82mA
800mV     -41.29mA   -30.53mA   -64.86mA
1.4V      -60.2mA    -43.81mA   -96.07mA
1.9V      -68.67mA   -49.13mA   -111.5mA
2.4V      -71.92mA   -50.95mA   -118.6mA
6.6V      -82.78mA   -58.05mA   -138.6mA
[GND_clamp]
|Voltage   I(typ)   I(min)   I(max)
-3.3V     -4.507A    -3.482A    -6.263A
-1.089V   -398.4mA   -420.6mA   -374.7mA
-1.022V   -290.7mA   -338.6mA   -230.6mA
-955mV    -191.4mA   -260.2mA   -120.1mA
-888mV    -107.5mA   -187mA     -73.69mA
-821mV    -53mA      -121.4mA   -59.83mA
-754mV    -31.41mA   -66.95mA   -47.44mA
-687mV    -21.17mA   -28.83mA   -34.23mA
-620mV    -13.21mA   -10.24mA   -21.98mA
-553mV    -6.877mA   -3.592mA   -11.71mA
-352mV    -122.8uA   -54.62uA   -209.3uA
3.3V      0A         0A         0A
[POWER_clamp]
|Voltage   I(typ)   I(min)   I(max)
-3.3V     59.07mA    46.89mA    89.53mA
-1.993V   37.2mA     28.86mA    58.21mA
-1.926V   35.72mA    27.66mA    56.06mA
-1.591V   27.94mA    21.43mA    44.69mA
-1.189V   17.87mA    13.66mA    29.79mA
-1.122V   16.12mA    12.35mA    27.17mA
-921mV    10.77mA    8.455mA    19.02mA
-586mV    1.798mA    2.256mA    3.367mA
-519mV    726.5uA    1.214mA    1.405mA
-452mV    229.1uA    443uA      409.2uA
-251mV    5.569uA    5.296uA    9.168uA
3.3V      0A         0A         0A
[Ramp]
| variable   typ   min   max
dV/dt_r   1.409/0.327n   1.186/0.554n   1.681/0.175n
dV/dt_f   1.453/0.564n   1.187/0.981n   1.695/0.307n
R_load = 50.000
[Rising Waveform]
R_fixture= 50.000
V_fixture= 0.0
V_fixture_min= 0.0
V_fixture_max= 0.0
|time   V(typ)   V(min)   V(max)
0s        12.56nV    33.46nV    156.1nV
661ps     270.8uV    -6.345uV   3.892mV
966ps     -44.88mV   131.8uV    2.418V
1.178ns   116.3mV    -129.2uV   2.706V
1.39ns    1.029V     -36.65mV   2.762V
1.606ns   1.888V     -27.29mV   2.784V
1.821ns   2.186V     39.12mV    2.793V
2.59ns    2.334V     1.588V     2.801V
3.515ns   2.348V     1.944V     2.802V
20ns      2.349V     1.976V     2.802V
[Rising Waveform]
R_fixture= 50.000
V_fixture= 3.300
V_fixture_min= 3.140
V_fixture_max= 3.470
|time   V(typ)   V(min)   V(max)
0s        878.1mV    1.161V     645.8mV
514ps     878.1mV    1.161V     665.1mV
802ps     870mV      1.161V     3.177V
858ps     989.1mV    1.161V     3.324V
1.111ns   2.552V     1.162V     3.436V
1.307ns   3.108V     1.222V     3.454V
1.469ns   3.23V      2.119V     3.461V
1.633ns   3.264V     2.631V     3.465V
2.283ns   3.295V     3.1V       3.469V
20ns      3.3V       3.14V      3.47V
[Falling Waveform]
R_fixture= 50.000
V_fixture= 3.300
V_fixture_min= 3.140
V_fixture_max= 3.470
|time   V(typ)   V(min)   V(max)
0s        3.3V       3.14V      3.47V
668ps     3.299V     3.14V      3.505V
1.153ns   3.311V     3.139V     1.067V
1.308ns   3.019V     3.14V      787.7mV
1.613ns   2.118V     3.222V     683.9mV
1.965ns   1.329V     3.113V     656.4mV
2.331ns   1.002V     2.667V     648.9mV
3.236ns   891.5mV    1.575V     646mV
4.342ns   879.5mV    1.218V     645.8mV
20ns      878mV      1.161V     645.8mV
[Falling Waveform]
R_fixture= 50.000
V_fixture= 0.0
V_fixture_min= 0.0
V_fixture_max= 0.0
|time   V(typ)   V(min)   V(max)
0s        2.349V     1.976V     2.802V
533ps     2.349V     1.976V     2.792V
635ps     2.349V     1.976V     1.755V
830ps     2.352V     1.976V     356.1mV
920ps     2.219V     1.976V     111.2mV
1.104ns   968.8mV    1.976V     32.74mV
1.481ns   86.75mV    1.933V     7.27mV
1.778ns   20.62mV    619.7mV    2.553mV
2.427ns   3.086mV    39.1mV     303.4uV
20ns      19.28nV    99.97nV    155nV
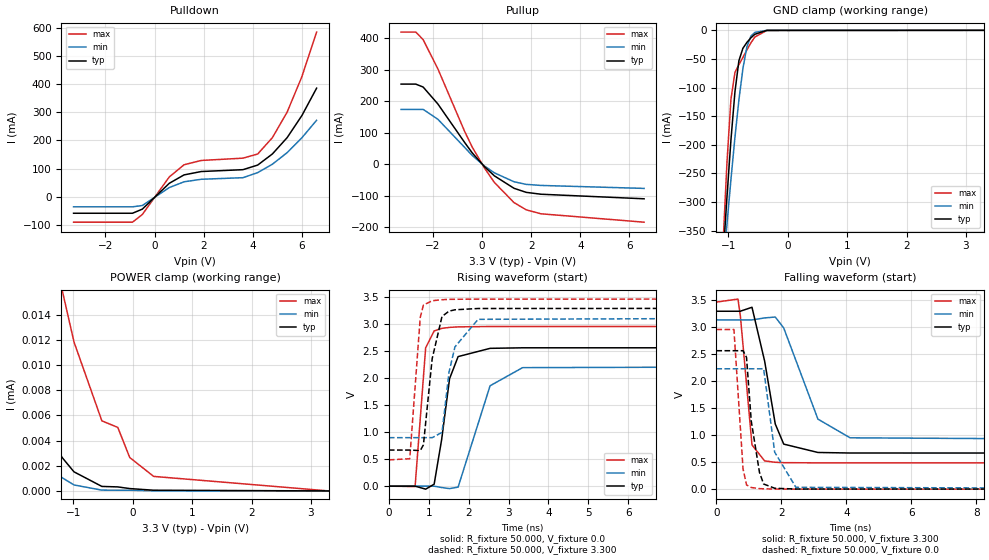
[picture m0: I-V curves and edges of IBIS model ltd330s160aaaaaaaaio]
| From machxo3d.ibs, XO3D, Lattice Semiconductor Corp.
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|   Model ltd330s160aaaaaaaaio
[Model] ltd330s160aaaaaaaaio
Model_type I/O
Polarity   Non-Inverting
Enable   Active-Low
Vinl =  0.800V
Vinh =  2.000V
Vmeas =  1.650V
Cref =  0.0F
Rref =  1.000M
Vref =  0.0V
C_comp   4.200pF   3.800pF   7.500pF
[Temperature Range]   25.000   0.105k   -40.000
[Voltage Range]   3.300V   3.140V   3.470V
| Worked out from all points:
|   slope of the pulldown table from 0 to 0.495 V, typ, clamps not added: 12.2 ohm
|   slope of the pullup table from 0 to 0.495 V, typ, clamps not added: 13.4 ohm
|   GND clamp passes 1 mA (typ) near -0.43 V on its own axis
|   rising waveform, R_fixture 50.000, V_fixture 0.0: 20-80 % time 280ps typ, 483ps min, 148ps max; typ from 0 V to 2.57 V
|   rising waveform, R_fixture 50.000, V_fixture 3.300: 20-80 % time 283ps typ, 331ps min, 179ps max; typ from 0.669 V to 3.3 V
|   falling waveform, R_fixture 50.000, V_fixture 3.300: 20-80 % time 458ps typ, 824ps min, 249ps max; typ from 3.3 V to 0.669 V
|   falling waveform, R_fixture 50.000, V_fixture 0.0: 20-80 % time 289ps typ, 349ps min, 195ps max; typ from 2.57 V to 0 V
[Pulldown]
|Voltage   I(typ)   I(min)   I(max)
-3.3V     -58.64mA   -35.81mA   -90.41mA
-900mV    -58.64mA   -35.81mA   -90.41mA
-500mV    -44.08mA   -31.23mA   -63.19mA
600mV     47.81mA    32.63mA    70.46mA
1.2V      77.59mA    53.08mA    113.6mA
1.9V      89.57mA    62.1mA     128.9mA
3.6V      96.17mA    67.69mA    137.1mA
4.2V      112.5mA    85.73mA    151.8mA
4.8V      152.1mA    115.6mA    210mA
5.4V      210mA      156.7mA    300.7mA
6V        288.3mA    209.5mA    426.5mA
6.6V      385.7mA    271.6mA    585mA
[Pullup]
|Voltage   I(typ)   I(min)   I(max)
-3.3V     254.2mA    173.8mA    419.6mA
-2.7V     254.2mA    173.8mA    419.6mA
-2.4V     244.9mA    173.8mA    395.6mA
-1.8V     191mA      142.4mA    302.6mA
-700mV    67.54mA    52.19mA    102.1mA
-400mV    35.48mA    27.29mA    53.85mA
100mV     -8.293mA   -6.216mA   -12.85mA
500mV     -37.38mA   -27.82mA   -58.35mA
1.3V      -76.97mA   -56.19mA   -122.5mA
1.8V      -89.97mA   -64.6mA    -145.5mA
2.4V      -95.89mA   -67.94mA   -158.1mA
6.6V      -110.4mA   -77.4mA    -184.8mA
[GND_clamp]
|Voltage   I(typ)   I(min)   I(max)
-3.3V     -4.507A    -3.482A    -6.263A
-1.089V   -398.4mA   -420.6mA   -374.7mA
-1.022V   -290.7mA   -338.6mA   -230.6mA
-955mV    -191.4mA   -260.2mA   -120.1mA
-888mV    -107.5mA   -187mA     -73.69mA
-821mV    -53mA      -121.4mA   -59.83mA
-754mV    -31.41mA   -66.95mA   -47.44mA
-687mV    -21.17mA   -28.83mA   -34.23mA
-620mV    -13.21mA   -10.24mA   -21.98mA
-553mV    -6.877mA   -3.592mA   -11.71mA
-352mV    -122.8uA   -54.62uA   -209.3uA
3.3V      0A         0A         0A
[POWER_clamp]
|Voltage   I(typ)   I(min)   I(max)
-3.3V     530uA      347.3uA    956.2uA
-2.663V   63.57uA    15.44uA    254.2uA
-2.529V   27.42uA    10.98uA    148.7uA
-2.328V   15.78uA    8.532uA    64.82uA
-1.725V   7.398uA    3.714uA    31uA
-1.189V   2.659uA    1.053uA    15.99uA
-988mV    1.516uA    474.5nA    11.83uA
-519mV    357.5nA    63.32nA    5.567uA
-251mV    319nA      55.58nA    5.047uA
-50mV     187.6nA    55.58nA    2.655uA
352mV     56.19nA    7.349nA    1.154uA
3.3V      0A         0A         0A
[Ramp]
| variable   typ   min   max
dV/dt_r   1.541/0.277n   1.340/0.480n   1.777/0.147n
dV/dt_f   1.578/0.460n   1.345/0.823n   1.789/0.248n
R_load = 50.000
[Rising Waveform]
R_fixture= 50.000
V_fixture= 0.0
V_fixture_min= 0.0
V_fixture_max= 0.0
|time   V(typ)   V(min)   V(max)
0s        9.963nV    27.08nV    122nV
657ps     222.8uV    14.35uV    -7.9mV
922ps     -55.86mV   38.37uV    2.566V
1.135ns   36.66mV    -53.64uV   2.879V
1.323ns   864mV      -25.29mV   2.926V
1.522ns   1.994V     -46.03mV   2.945V
1.736ns   2.403V     -17.21mV   2.954V
2.538ns   2.556V     1.862V     2.961V
3.353ns   2.566V     2.198V     2.961V
20ns      2.568V     2.233V     2.961V
[Rising Waveform]
R_fixture= 50.000
V_fixture= 3.300
V_fixture_min= 3.140
V_fixture_max= 3.470
|time   V(typ)   V(min)   V(max)
0s        669.4mV    899.2mV    487.7mV
523ps     669.4mV    899.2mV    508.1mV
787ps     659.5mV    899.2mV    3.134V
866ps     766.6mV    899.2mV    3.359V
1.085ns   2.362V     899.5mV    3.439V
1.332ns   3.147V     997.2mV    3.458V
1.508ns   3.246V     2.114V     3.464V
1.657ns   3.271V     2.584V     3.466V
2.237ns   3.295V     3.094V     3.469V
20ns      3.3V       3.14V      3.47V
[Falling Waveform]
R_fixture= 50.000
V_fixture= 3.300
V_fixture_min= 3.140
V_fixture_max= 3.470
|time   V(typ)   V(min)   V(max)
0s        3.3V       3.14V      3.47V
664ps     3.3V       3.14V      3.526V
739ps     3.301V     3.14V      3.206V
1.095ns   3.374V     3.14V      820mV
1.484ns   2.375V     3.176V     524.8mV
1.811ns   1.209V     3.193V     498.6mV
2.071ns   835.8mV    2.99V      491.9mV
3.124ns   680.5mV    1.299V     487.8mV
4.113ns   670.7mV    952.6mV    487.6mV
20ns      669.4mV    899.1mV    487.5mV
[Falling Waveform]
R_fixture= 50.000
V_fixture= 0.0
V_fixture_min= 0.0
V_fixture_max= 0.0
|time   V(typ)   V(min)   V(max)
0s        2.568V     2.233V     2.961V
539ps     2.568V     2.233V     2.961V
820ps     2.568V     2.233V     375.8mV
927ps     2.444V     2.233V     78.45mV
1.072ns   1.265V     2.233V     30.59mV
1.325ns   311.4mV    2.232V     10.57mV
1.453ns   95.63mV    2.235V     6.745mV
1.794ns   16.91mV    685.6mV    1.962mV
2.446ns   2.663mV    34.59mV    216uV
20ns      16.91nV    85.18nV    121.7nV
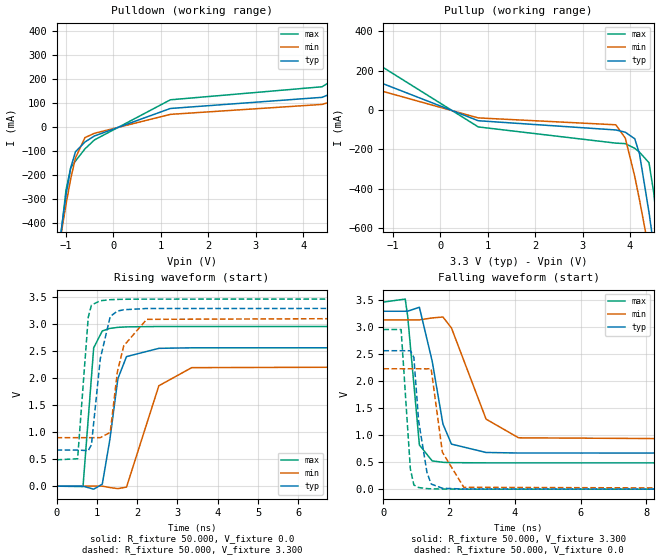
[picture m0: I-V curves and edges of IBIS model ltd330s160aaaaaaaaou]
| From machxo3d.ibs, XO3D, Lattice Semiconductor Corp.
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|   Model ltd330s160aaaaaaaaou
[Model] ltd330s160aaaaaaaaou
Model_type Output
Polarity   Non-Inverting
Enable   Active-High
Vmeas =  1.650V
Cref =  0.0F
Rref =  1.000M
Vref =  0.0V
C_comp   4.200pF   3.800pF   7.500pF
[Temperature Range]   25.000   0.105k   -40.000
[Voltage Range]   3.300V   3.140V   3.470V
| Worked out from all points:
|   slope of the pulldown table from 0 to 0.495 V, typ, clamps not added: 12.2 ohm
|   slope of the pullup table from 0 to 0.495 V, typ, clamps not added: 13.4 ohm
|   rising waveform, R_fixture 50.000, V_fixture 0.0: 20-80 % time 280ps typ, 483ps min, 148ps max; typ from 0 V to 2.57 V
|   rising waveform, R_fixture 50.000, V_fixture 3.300: 20-80 % time 283ps typ, 333ps min, 179ps max; typ from 0.669 V to 3.3 V
|   falling waveform, R_fixture 50.000, V_fixture 3.300: 20-80 % time 458ps typ, 824ps min, 249ps max; typ from 3.3 V to 0.669 V
|   falling waveform, R_fixture 50.000, V_fixture 0.0: 20-80 % time 289ps typ, 349ps min, 195ps max; typ from 2.57 V to 0 V
[Pulldown]
|Voltage   I(typ)   I(min)   I(max)
-3.3V     -4.508A    -3.483A    -6.264A
-1.1V     -430mA     -440.6mA   -433.4mA
-1V       -282.5mA   -321.4mA   -261.3mA
-900mV    -168.1mA   -213.9mA   -168.3mA
-800mV    -102.2mA   -127.5mA   -140.7mA
-600mV    -61.61mA   -43.3mA    -90.2mA
-400mV    -36.61mA   -25.5mA    -52.98mA
1.2V      77.59mA    53.08mA    113.6mA
4.4V      123.9mA    94.46mA    167.8mA
5.2V      188.5mA    141.7mA    266.7mA
6V        288.4mA    209.6mA    426.6mA
6.6V      386.2mA    272.1mA    585.7mA
[Pullup]
|Voltage   I(typ)   I(min)   I(max)
-3.3V     254.3mA    173.8mA    419.8mA
-2.4V     244.9mA    173.8mA    395.6mA
800mV     -55.05mA   -40.71mA   -86.48mA
3.7V      -101.9mA   -75.69mA   -168.8mA
3.9V      -113.4mA   -143.5mA   -171.5mA
4.1V      -146.7mA   -338.6mA   -195.2mA
4.2V      -224.4mA   -457.7mA   -214.8mA
4.4V      -521mA     -713.3mA   -268.6mA
4.5V      -691.6mA   -845.9mA   -420.8mA
4.6V      -867.9mA   -980.3mA   -645.1mA
4.7V      -1.048A    -1.116A    -890.7mA
6.6V      -4.617A    -3.787A    -5.985A
[Ramp]
| variable   typ   min   max
dV/dt_r   1.541/0.277n   1.340/0.480n   1.777/0.147n
dV/dt_f   1.578/0.460n   1.345/0.823n   1.789/0.248n
R_load = 50.000
[Rising Waveform]
R_fixture= 50.000
V_fixture= 0.0
V_fixture_min= 0.0
V_fixture_max= 0.0
|time   V(typ)   V(min)   V(max)
0s        9.963nV    27.08nV    122nV
657ps     222.8uV    14.41uV    -7.9mV
922ps     -55.86mV   38.38uV    2.566V
1.135ns   36.66mV    -53.65uV   2.879V
1.323ns   864mV      -25.29mV   2.926V
1.522ns   1.994V     -46.03mV   2.945V
1.736ns   2.403V     -17.21mV   2.954V
2.538ns   2.556V     1.862V     2.961V
3.353ns   2.566V     2.198V     2.961V
20ns      2.568V     2.233V     2.961V
[Rising Waveform]
R_fixture= 50.000
V_fixture= 3.300
V_fixture_min= 3.140
V_fixture_max= 3.470
|time   V(typ)   V(min)   V(max)
0s        669.4mV    899.2mV    487.7mV
523ps     669.4mV    899.2mV    508.1mV
787ps     659.5mV    899.2mV    3.134V
866ps     766.6mV    899.2mV    3.359V
1.085ns   2.362V     899.5mV    3.439V
1.332ns   3.147V     997.2mV    3.458V
1.508ns   3.246V     2.114V     3.464V
1.667ns   3.272V     2.603V     3.466V
2.237ns   3.295V     3.094V     3.469V
20ns      3.3V       3.14V      3.47V
[Falling Waveform]
R_fixture= 50.000
V_fixture= 3.300
V_fixture_min= 3.140
V_fixture_max= 3.470
|time   V(typ)   V(min)   V(max)
0s        3.3V       3.14V      3.47V
664ps     3.3V       3.14V      3.526V
739ps     3.301V     3.14V      3.206V
1.095ns   3.374V     3.14V      820mV
1.484ns   2.375V     3.176V     524.8mV
1.811ns   1.209V     3.193V     498.6mV
2.071ns   835.8mV    2.99V      491.9mV
3.124ns   680.5mV    1.299V     487.8mV
4.113ns   670.7mV    952.6mV    487.6mV
20ns      669.4mV    899.1mV    487.5mV
[Falling Waveform]
R_fixture= 50.000
V_fixture= 0.0
V_fixture_min= 0.0
V_fixture_max= 0.0
|time   V(typ)   V(min)   V(max)
0s        2.568V     2.233V     2.961V
539ps     2.568V     2.233V     2.961V
820ps     2.568V     2.233V     375.8mV
927ps     2.444V     2.233V     78.45mV
1.072ns   1.265V     2.233V     30.59mV
1.325ns   311.4mV    2.232V     10.57mV
1.453ns   95.63mV    2.235V     6.745mV
1.794ns   16.91mV    685.6mV    1.962mV
2.446ns   2.663mV    34.59mV    216uV
20ns      16.91nV    85.18nV    121.7nV
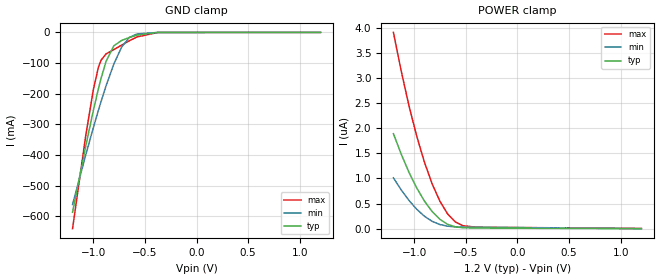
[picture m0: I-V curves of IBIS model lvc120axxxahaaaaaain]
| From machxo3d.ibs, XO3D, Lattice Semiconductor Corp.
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|   Model lvc120axxxahaaaaaain
[Model] lvc120axxxahaaaaaain
Model_type Input
Polarity   Non-Inverting
Enable   Active-High
Vinl =  0.420V
Vinh =  0.780V
C_comp   4.200pF   3.800pF   7.500pF
[Temperature Range]   25.000   0.105k   -40.000
[Voltage Range]   1.200V   1.140V   1.260V
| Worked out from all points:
|   GND clamp passes 1 mA (typ) near -0.44 V on its own axis
[GND_clamp]
|Voltage   I(typ)   I(min)   I(max)
-1.2V     -586.8mA   -561.6mA   -640.3mA
-1.075V   -375.3mA   -403.2mA   -342.9mA
-1V       -256.8mA   -312.3mA   -188.8mA
-950mV    -184.3mA   -254.5mA   -114.1mA
-925mV    -151.1mA   -226.6mA   -91.26mA
-875mV    -93.95mA   -173.6mA   -69.99mA
-800mV    -43.5mA    -102.9mA   -56.04mA
-725mV    -26.4mA    -48.03mA   -41.57mA
-650mV    -16.5mA    -16.35mA   -27.16mA
-575mV    -8.667mA   -5.012mA   -14.69mA
-375mV    -183.5uA   -82.46uA   -270.8uA
1.2V      0A         0A         0A
[POWER_clamp]
|Voltage   I(typ)   I(min)   I(max)
-1.2V     1.889uA    1.011uA    3.905uA
-1.125V   1.485uA    772.5nA    3.141uA
-1.05V    1.124uA    563.1nA    2.451uA
-975mV    812.1nA    387.4nA    1.845uA
-900mV    550.1nA    247.6nA    1.324uA
-825mV    340.1nA    145.7nA    890.5nA
-750mV    184.9nA    81.65nA    545.5nA
-675mV    85.57nA    49.12nA    292.2nA
-600mV    35.86nA    36nA       132.8nA
-525mV    17.85nA    31.3nA     57.8nA
-400mV    11.64nA    28.64nA    28.95nA
1.2V      0A         0A         3.808nA
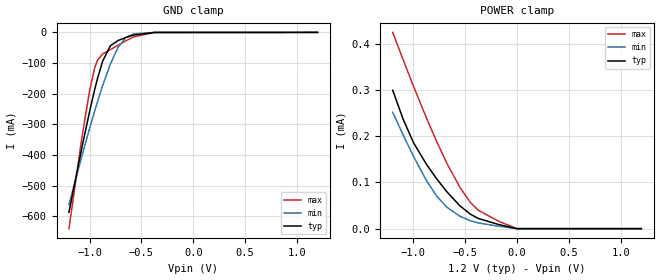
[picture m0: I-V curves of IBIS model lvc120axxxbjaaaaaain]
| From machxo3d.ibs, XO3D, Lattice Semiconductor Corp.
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|   Model lvc120axxxbjaaaaaain
[Model] lvc120axxxbjaaaaaain
Model_type Input
Polarity   Non-Inverting
Enable   Active-High
Vinl =  0.420V
Vinh =  0.780V
C_comp   4.200pF   3.800pF   7.500pF
[Temperature Range]   25.000   0.105k   -40.000
[Voltage Range]   1.200V   1.140V   1.260V
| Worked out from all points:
|   GND clamp passes 1 mA (typ) near -0.44 V on its own axis
[GND_clamp]
|Voltage   I(typ)   I(min)   I(max)
-1.2V     -586.8mA   -561.6mA   -640.3mA
-1.075V   -375.3mA   -403.2mA   -342.9mA
-1V       -256.8mA   -312.3mA   -188.8mA
-950mV    -184.3mA   -254.5mA   -114mA
-925mV    -151.1mA   -226.6mA   -91.27mA
-875mV    -93.95mA   -173.6mA   -70mA
-800mV    -43.51mA   -102.9mA   -56.05mA
-725mV    -26.4mA    -48.03mA   -41.58mA
-650mV    -16.51mA   -16.35mA   -27.17mA
-575mV    -8.674mA   -5.016mA   -14.71mA
-375mV    -194.8uA   -87.66uA   -296.2uA
1.2V      -42.59nA   0A         -5.33uA
[POWER_clamp]
|Voltage   I(typ)   I(min)   I(max)
-1.2V     299.6uA    251.9uA    424.8uA
-1.1V     237.3uA    203.2uA    366uA
-1V       186.4uA    156.9uA    308.7uA
-875mV    139.5uA    104.5uA    239.9uA
-775mV    107.7uA    70.18uA    188.3uA
-675mV    79.18uA    45.9uA     140.6uA
-550mV    49.19uA    26.84uA    88.83uA
-450mV    31.3uA     17.16uA    56.66uA
-375mV    22.16uA    12.38uA    40.11uA
-175mV    8.775uA    5.159uA    15.8uA
0V        3.648nA    7.361nA    0A
1.2V      0A         0A         0A
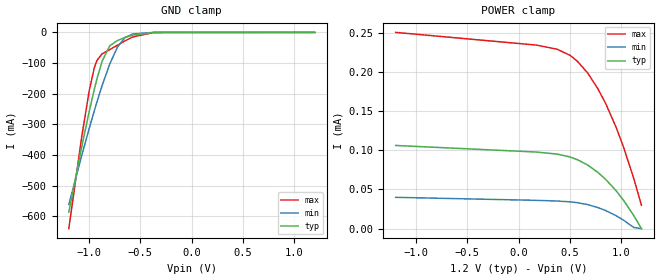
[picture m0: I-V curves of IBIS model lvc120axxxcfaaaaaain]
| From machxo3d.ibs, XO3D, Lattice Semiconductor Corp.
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|   Model lvc120axxxcfaaaaaain
[Model] lvc120axxxcfaaaaaain
Model_type Input
Polarity   Non-Inverting
Enable   Active-High
Vinl =  0.420V
Vinh =  0.780V
C_comp   4.200pF   3.800pF   7.500pF
[Temperature Range]   25.000   0.105k   -40.000
[Voltage Range]   1.200V   1.140V   1.260V
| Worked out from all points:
|   GND clamp passes 1 mA (typ) near -0.44 V on its own axis
[GND_clamp]
|Voltage   I(typ)   I(min)   I(max)
-1.2V     -586.8mA   -561.7mA   -640.4mA
-1.075V   -375.3mA   -403.2mA   -342.9mA
-1V       -256.8mA   -312.4mA   -188.9mA
-950mV    -184.3mA   -254.5mA   -114.1mA
-925mV    -151.1mA   -226.6mA   -91.32mA
-875mV    -94.01mA   -173.6mA   -70.06mA
-800mV    -43.56mA   -102.9mA   -56.11mA
-725mV    -26.45mA   -48.06mA   -41.65mA
-650mV    -16.55mA   -16.39mA   -27.24mA
-575mV    -8.728mA   -5.059mA   -14.79mA
-375mV    -266.5uA   -129.3uA   -404.6uA
1.2V      0A         0A         0A
[POWER_clamp]
|Voltage   I(typ)   I(min)   I(max)
-1.2V     106.1uA    39.97uA    250.3uA
175mV     97.7uA     36.09uA    234.1uA
375mV     95.13uA    35.25uA    228.9uA
500mV     91.53uA    34.24uA    221.3uA
575mV     87.92uA    33.12uA    213.4uA
675mV     81.09uA    30.65uA    198.5uA
775mV     71.72uA    26.88uA    178.3uA
850mV     62.93uA    23.1uA     159.7uA
950mV     48.73uA    16.7uA     130.1uA
1.025V    36.14uA    10.83uA    104uA
1.125V    16.67uA    1.54uA     64.01uA
1.2V      0A         0A         29.9uA
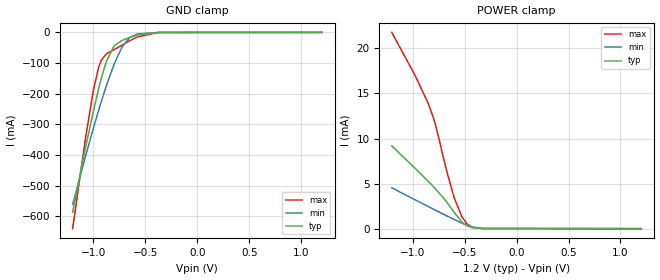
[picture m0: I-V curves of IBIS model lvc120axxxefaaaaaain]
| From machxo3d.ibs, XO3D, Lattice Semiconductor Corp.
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|   Model lvc120axxxefaaaaaain
[Model] lvc120axxxefaaaaaain
Model_type Input
Polarity   Non-Inverting
Enable   Active-High
Vinl =  0.420V
Vinh =  0.780V
C_comp   4.200pF   3.800pF   7.500pF
[Temperature Range]   25.000   0.105k   -40.000
[Voltage Range]   1.200V   1.140V   1.260V
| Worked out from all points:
|   GND clamp passes 1 mA (typ) near -0.44 V on its own axis
|   POWER clamp passes 1 mA (typ) near -0.55 V on its own axis
[GND_clamp]
|Voltage   I(typ)   I(min)   I(max)
-1.2V     -586.8mA   -561.6mA   -640.3mA
-1.075V   -375.3mA   -403.2mA   -342.9mA
-1V       -256.8mA   -312.3mA   -188.8mA
-950mV    -184.3mA   -254.5mA   -114.1mA
-925mV    -151.1mA   -226.6mA   -91.26mA
-875mV    -93.95mA   -173.6mA   -69.99mA
-800mV    -43.5mA    -102.9mA   -56.04mA
-725mV    -26.4mA    -48.03mA   -41.57mA
-650mV    -16.5mA    -16.35mA   -27.16mA
-575mV    -8.667mA   -5.012mA   -14.69mA
-375mV    -183.5uA   -82.46uA   -270.8uA
1.2V      0A         0A         0A
[POWER_clamp]
|Voltage   I(typ)   I(min)   I(max)
-1.2V     9.182mA    4.531mA    21.77mA
-975mV    6.68mA     3.195mA    16.97mA
-850mV    5.256mA    2.452mA    13.9mA
-800mV    4.662mA    2.159mA    12.31mA
-775mV    4.355mA    2.014mA    11.32mA
-675mV    3.015mA    1.438mA    6.52mA
-600mV    1.813mA    1.015mA    3.43mA
-525mV    717.6uA    612.9uA    1.296mA
-475mV    302.2uA    372.2uA    507.9uA
-425mV    111uA      180.2uA    159.4uA
-325mV    13.15uA    20.51uA    12.23uA
1.2V      0A         0A         3.808nA
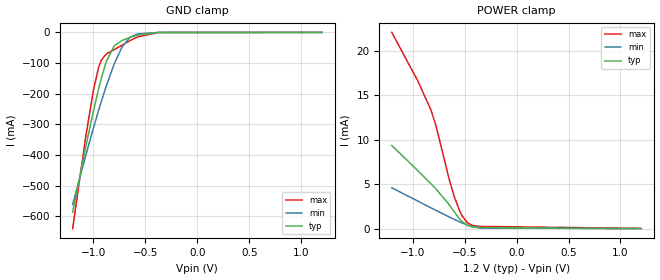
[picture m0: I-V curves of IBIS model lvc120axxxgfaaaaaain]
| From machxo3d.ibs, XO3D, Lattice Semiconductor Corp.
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|   Model lvc120axxxgfaaaaaain
[Model] lvc120axxxgfaaaaaain
Model_type Input
Polarity   Non-Inverting
Enable   Active-High
Vinl =  0.420V
Vinh =  0.780V
C_comp   4.200pF   3.800pF   7.500pF
[Temperature Range]   25.000   0.105k   -40.000
[Voltage Range]   1.200V   1.140V   1.260V
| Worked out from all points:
|   GND clamp passes 1 mA (typ) near -0.44 V on its own axis
|   POWER clamp passes 1 mA (typ) near -0.54 V on its own axis
[GND_clamp]
|Voltage   I(typ)   I(min)   I(max)
-1.2V     -586.8mA   -561.7mA   -640.4mA
-1.075V   -375.3mA   -403.2mA   -342.9mA
-1V       -256.8mA   -312.4mA   -188.9mA
-950mV    -184.3mA   -254.5mA   -114.1mA
-925mV    -151.1mA   -226.6mA   -91.32mA
-875mV    -94.01mA   -173.6mA   -70.06mA
-800mV    -43.56mA   -102.9mA   -56.11mA
-725mV    -26.45mA   -48.06mA   -41.65mA
-650mV    -16.55mA   -16.39mA   -27.24mA
-575mV    -8.728mA   -5.059mA   -14.79mA
-375mV    -266.5uA   -129.3uA   -404.6uA
1.2V      0A         0A         0A
[POWER_clamp]
|Voltage   I(typ)   I(min)   I(max)
-1.2V     9.358mA    4.601mA    22.1mA
-950mV    6.537mA    3.101mA    16.64mA
-825mV    5.08mA     2.355mA    13.4mA
-775mV    4.466mA    2.06mA     11.6mA
-650mV    2.734mA    1.335mA    5.647mA
-600mV    1.907mA    1.053mA    3.642mA
-550mV    1.113mA    778.7uA    2.069mA
-525mV    798uA      647.5uA    1.472mA
-475mV    381.7uA    406uA      682.4uA
-425mV    196.4uA    214.2uA    354.3uA
-350mV    117.6uA    72.69uA    251.1uA
1.2V      0A         0A         29.9uA
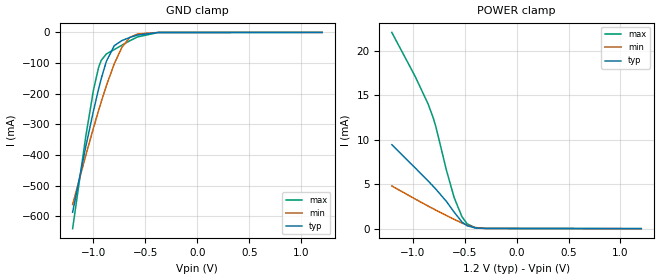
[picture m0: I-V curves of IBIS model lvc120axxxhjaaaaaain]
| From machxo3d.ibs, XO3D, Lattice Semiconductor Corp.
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|   Model lvc120axxxhjaaaaaain
[Model] lvc120axxxhjaaaaaain
Model_type Input
Polarity   Non-Inverting
Enable   Active-High
Vinl =  0.420V
Vinh =  0.780V
C_comp   4.200pF   3.800pF   7.500pF
[Temperature Range]   25.000   0.105k   -40.000
[Voltage Range]   1.200V   1.140V   1.260V
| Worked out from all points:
|   GND clamp passes 1 mA (typ) near -0.44 V on its own axis
|   POWER clamp passes 1 mA (typ) near -0.55 V on its own axis
[GND_clamp]
|Voltage   I(typ)   I(min)   I(max)
-1.2V     -586.8mA   -561.7mA   -640.4mA
-1.075V   -375.3mA   -403.2mA   -342.9mA
-1V       -256.8mA   -312.4mA   -188.9mA
-950mV    -184.3mA   -254.5mA   -114.1mA
-925mV    -151.1mA   -226.6mA   -91.32mA
-875mV    -94.01mA   -173.6mA   -70.06mA
-800mV    -43.56mA   -102.9mA   -56.11mA
-725mV    -26.45mA   -48.06mA   -41.65mA
-650mV    -16.55mA   -16.39mA   -27.24mA
-575mV    -8.728mA   -5.059mA   -14.79mA
-375mV    -266.5uA   -129.3uA   -404.6uA
1.2V      -42.59nA   0A         -5.33uA
[POWER_clamp]
|Voltage   I(typ)   I(min)   I(max)
-1.2V     9.441mA    4.803mA    22.07mA
-975mV    6.83mA     3.329mA    17.11mA
-850mV    5.356mA    2.536mA    14mA
-800mV    4.744mA    2.228mA    12.4mA
-775mV    4.43mA     2.076mA    11.41mA
-675mV    3.065mA    1.478mA    6.596mA
-600mV    1.851mA    1.044mA    3.486mA
-525mV    744.7uA    632.6uA    1.337mA
-475mV    325.6uA    388.1uA    543.5uA
-400mV    86.39uA    124.7uA    120.1uA
-300mV    23.03uA    20.03uA    34.62uA
1.2V      0A         0A         0A
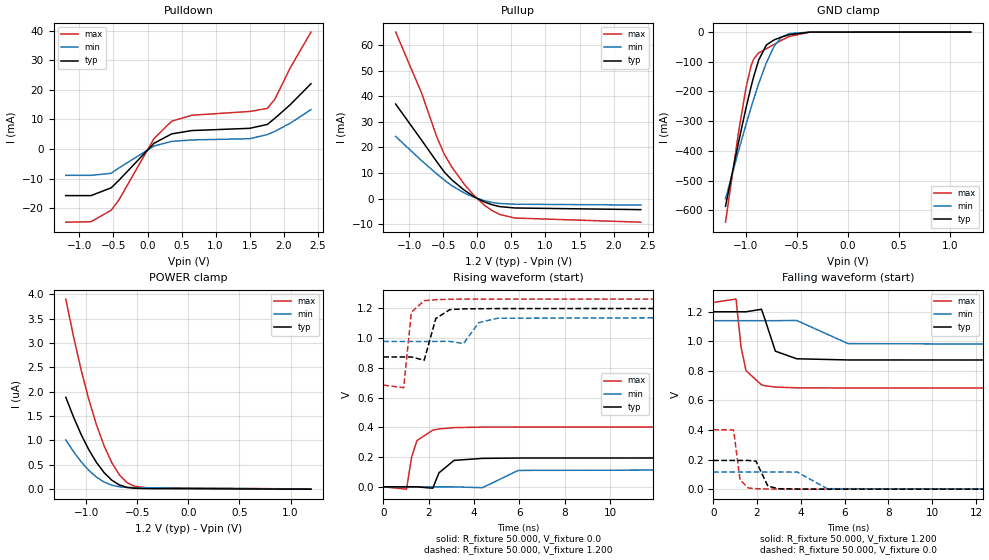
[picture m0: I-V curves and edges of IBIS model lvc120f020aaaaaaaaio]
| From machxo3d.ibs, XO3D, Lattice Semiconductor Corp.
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|   Model lvc120f020aaaaaaaaio
[Model] lvc120f020aaaaaaaaio
Model_type I/O
Polarity   Non-Inverting
Enable   Active-Low
Vinl =  0.420V
Vinh =  0.780V
Vmeas =  0.600V
Cref =  0.0F
Rref =  1.000M
Vref =  0.0V
C_comp   4.200pF   3.800pF   7.500pF
[Temperature Range]   25.000   0.105k   -40.000
[Voltage Range]   1.200V   1.140V   1.260V
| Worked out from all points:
|   slope of the pulldown table from 0 to 0.18 V, typ, clamps not added: 55.1 ohm
|   slope of the pullup table from 0 to 0.18 V, typ, clamps not added: 85.3 ohm
|   GND clamp passes 1 mA (typ) near -0.44 V on its own axis
|   rising waveform, R_fixture 50.000, V_fixture 0.0: 20-80 % time 406ps typ, 579ps min, 397ps max; typ from 0 V to 0.194 V
|   rising waveform, R_fixture 50.000, V_fixture 1.200: 20-80 % time 338ps typ, 491ps min, 207ps max; typ from 0.873 V to 1.2 V
|   falling waveform, R_fixture 50.000, V_fixture 1.200: 20-80 % time 432ps typ, 614ps min, 349ps max; typ from 1.2 V to 0.873 V
|   falling waveform, R_fixture 50.000, V_fixture 0.0: 20-80 % time 333ps typ, 500ps min, 181ps max; typ from 0.194 V to 0 V
[Pulldown]
|Voltage   I(typ)   I(min)   I(max)
-1.2V     -15.77mA   -8.921mA   -24.76mA
-830mV    -15.77mA   -8.921mA   -24.61mA
-534mV    -13.14mA   -8.234mA   -20.74mA
-423mV    -10.67mA   -6.463mA   -17.35mA
95mV      1.91mA     997.3uA    3.496mA
354mV     5.095mA    2.558mA    9.38mA
650mV     6.221mA    3.05mA     11.4mA
1.501V    6.983mA    3.464mA    12.68mA
1.76V     8.298mA    4.874mA    13.72mA
1.871V    10.4mA     5.962mA    16.85mA
2.093V    14.91mA    8.691mA    27.31mA
2.4V      22.06mA    13.29mA    39.52mA
[Pullup]
|Voltage   I(typ)   I(min)   I(max)
-1.2V     36.95mA    24.29mA    65.09mA
-819mV    22.83mA    14.81mA    41.26mA
-597mV    14.43mA    9.66mA     24.15mA
-486mV    10.38mA    7.228mA    17.33mA
-375mV    7.309mA    5.026mA    12.31mA
-190mV    3.229mA    2.154mA    5.518mA
-42mV     628.1uA    407.3uA    979.6uA
106mV     -1.356mA   -861.5uA   -2.669mA
217mV     -2.425mA   -1.522mA   -4.729mA
328mV     -3.145mA   -1.941mA   -6.218mA
550mV     -3.688mA   -2.208mA   -7.621mA
2.4V      -4.336mA   -2.552mA   -9.246mA
[GND_clamp]
|Voltage   I(typ)   I(min)   I(max)
-1.2V     -586.8mA   -561.6mA   -640.3mA
-1.075V   -375.3mA   -403.2mA   -342.9mA
-1V       -256.8mA   -312.3mA   -188.8mA
-950mV    -184.3mA   -254.5mA   -114.1mA
-925mV    -151.1mA   -226.6mA   -91.26mA
-875mV    -93.95mA   -173.6mA   -69.99mA
-800mV    -43.5mA    -102.9mA   -56.04mA
-725mV    -26.4mA    -48.03mA   -41.57mA
-650mV    -16.5mA    -16.35mA   -27.16mA
-575mV    -8.667mA   -5.012mA   -14.69mA
-375mV    -183.5uA   -82.46uA   -270.8uA
1.2V      0A         0A         0A
[POWER_clamp]
|Voltage   I(typ)   I(min)   I(max)
-1.2V     1.889uA    1.011uA    3.905uA
-1.125V   1.485uA    772.5nA    3.141uA
-1.05V    1.124uA    563.1nA    2.451uA
-975mV    812.1nA    387.4nA    1.845uA
-900mV    550.1nA    247.6nA    1.324uA
-825mV    340.1nA    145.7nA    890.5nA
-750mV    184.9nA    81.62nA    545.5nA
-675mV    85.57nA    49.09nA    292.2nA
-600mV    35.86nA    35.98nA    132.8nA
-525mV    17.85nA    31.28nA    57.79nA
-400mV    11.64nA    28.62nA    28.95nA
1.2V      0A         0A         3.808nA
[Ramp]
| variable   typ   min   max
dV/dt_r   0.117/0.430n   69.294m/0.574n   0.241/0.402n
dV/dt_f   0.196/0.434n   97.283m/0.595n   0.346/0.351n
R_load = 50.000
[Rising Waveform]
R_fixture= 50.000
V_fixture= 0.0
V_fixture_min= 0.0
V_fixture_max= 0.0
|time   V(typ)   V(min)   V(max)
0s        4.736nV    57.27nV    2.383nV
1.021ns   1.51uV     15.12uV    -15.74mV
1.244ns   174.9uV    15.12uV    200mV
1.483ns   28.63uV    -9.839uV   311.3mV
2.177ns   -9.564mV   64.72uV    381.1mV
2.454ns   94.49mV    163.3uV    389.7mV
3.119ns   177.9mV    -286uV     398.3mV
4.369ns   191.3mV    -5.829mV   401.6mV
5.949ns   193.7mV    110.4mV    402.2mV
20ns      194.3mV    115.5mV    402.3mV
[Rising Waveform]
R_fixture= 50.000
V_fixture= 1.200
V_fixture_min= 1.140
V_fixture_max= 1.260
|time   V(typ)   V(min)   V(max)
0s        873.4mV    977.9mV    684.3mV
895ps     873.4mV    977.9mV    666.9mV
1.233ns   873.5mV    977.9mV    1.174V
1.8ns     851.7mV    977.8mV    1.252V
2.312ns   1.132V     978.1mV    1.259V
2.931ns   1.192V     978.5mV    1.262V
3.537ns   1.197V     963.8mV    1.263V
4.202ns   1.198V     1.104V     1.263V
5.027ns   1.199V     1.134V     1.263V
20ns      1.2V       1.14V      1.263V
[Falling Waveform]
R_fixture= 50.000
V_fixture= 1.200
V_fixture_min= 1.140
V_fixture_max= 1.260
|time   V(typ)   V(min)   V(max)
0s        1.2V       1.14V      1.263V
1.041ns   1.2V       1.14V      1.286V
1.273ns   1.2V       1.14V      958.7mV
1.496ns   1.2V       1.14V      801.8mV
2.204ns   1.217V     1.14V      705.6mV
2.361ns   1.149V     1.14V      699.4mV
2.838ns   933.5mV    1.14V      690.9mV
3.812ns   882mV      1.141V     685.4mV
6.159ns   874.1mV    984.7mV    684.3mV
20ns      873.4mV    977.9mV    684.3mV
[Falling Waveform]
R_fixture= 50.000
V_fixture= 0.0
V_fixture_min= 0.0
V_fixture_max= 0.0
|time   V(typ)   V(min)   V(max)
0s        194.3mV    115.5mV    402.3mV
930ps     194.3mV    115.5mV    400.5mV
1.221ns   194.3mV    115.5mV    64.26mV
1.595ns   194.3mV    115.5mV    8.163mV
1.952ns   189.5mV    115.5mV    3.306mV
2.497ns   20.1mV     115.4mV    1.14mV
3.005ns   3.005mV    115.6mV    346.4uV
3.837ns   872.4uV    115.8mV    78.28uV
5.206ns   263.1uV    3.261mV    34.1uV
20ns      -183.3nV   -307.1nV   -123.9nV
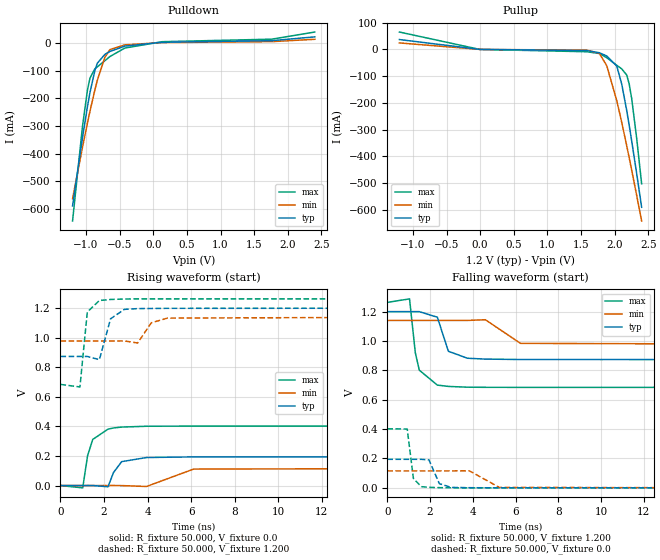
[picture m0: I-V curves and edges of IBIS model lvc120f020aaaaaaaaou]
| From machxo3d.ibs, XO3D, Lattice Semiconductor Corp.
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|   Model lvc120f020aaaaaaaaou
[Model] lvc120f020aaaaaaaaou
Model_type Output
Polarity   Non-Inverting
Enable   Active-High
Vmeas =  0.600V
Cref =  0.0F
Rref =  1.000M
Vref =  0.0V
C_comp   4.200pF   3.800pF   7.500pF
[Temperature Range]   25.000   0.105k   -40.000
[Voltage Range]   1.200V   1.140V   1.260V
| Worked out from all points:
|   slope of the pulldown table from 0 to 0.18 V, typ, clamps not added: 55.1 ohm
|   slope of the pullup table from 0 to 0.18 V, typ, clamps not added: 85.3 ohm
|   rising waveform, R_fixture 50.000, V_fixture 0.0: 20-80 % time 405ps typ, 582ps min, 395ps max; typ from 0 V to 0.194 V
|   rising waveform, R_fixture 50.000, V_fixture 1.200: 20-80 % time 337ps typ, 483ps min, 204ps max; typ from 0.873 V to 1.2 V
|   falling waveform, R_fixture 50.000, V_fixture 1.200: 20-80 % time 433ps typ, 603ps min, 348ps max; typ from 1.2 V to 0.873 V
|   falling waveform, R_fixture 50.000, V_fixture 0.0: 20-80 % time 333ps typ, 496ps min, 181ps max; typ from 0.194 V to 0 V
[Pulldown]
|Voltage   I(typ)   I(min)   I(max)
-1.2V     -588.5mA   -562.6mA   -643.2mA
-1.052V   -341.1mA   -376.3mA   -300.5mA
-978mV    -229mA     -288.4mA   -169.1mA
-941mV    -178.7mA   -246.5mA   -126.6mA
-867mV    -98.35mA   -168.4mA   -92.94mA
-830mV    -72.38mA   -133.3mA   -85.88mA
-719mV    -41.09mA   -51.67mA   -64.01mA
-645mV    -30.75mA   -23.95mA   -49.03mA
-423mV    -11.33mA   -6.73mA    -18.4mA
132mV     2.541mA    1.32mA     4.656mA
1.76V     8.299mA    4.874mA    13.72mA
2.4V      22.06mA    13.29mA    39.53mA
[Pullup]
|Voltage   I(typ)   I(min)   I(max)
-1.2V     36.95mA    24.29mA    65.1mA
-5mV      72.11uA    46.33uA    -26.46uA
1.586V    -4.313mA   -2.851mA   -8.695mA
1.771V    -12.45mA   -14.56mA   -15.38mA
1.882V    -24.63mA   -61.17mA   -31.07mA
2.03V     -62.24mA   -191.6mA   -59.45mA
2.104V    -129.6mA   -272.9mA   -72.75mA
2.178V    -228.3mA   -360.4mA   -95.8mA
2.215V    -284mA     -405.7mA   -129.1mA
2.252V    -342.3mA   -451.9mA   -183.9mA
2.326V    -464.4mA   -546.1mA   -332.1mA
2.4V      -591.1mA   -642.4mA   -503.2mA
[Ramp]
| variable   typ   min   max
dV/dt_r   0.117/0.429n   69.294m/0.573n   0.241/0.398n
dV/dt_f   0.196/0.410n   97.283m/0.584n   0.346/0.350n
R_load = 50.000
[Rising Waveform]
R_fixture= 50.000
V_fixture= 0.0
V_fixture_min= 0.0
V_fixture_max= 0.0
|time   V(typ)   V(min)   V(max)
0s        4.708nV    57.48nV    2.342nV
1.022ns   13.41uV    13.77uV    -15.58mV
1.246ns   188.3uV    13.77uV    202mV
1.483ns   75.14uV    13.77uV    312.2mV
2.185ns   -8.253mV   64uV       381.7mV
2.434ns   87.54mV    167uV      389.6mV
2.811ns   161.7mV    -217.7uV   395.6mV
3.95ns    189.6mV    -6.395mV   401.2mV
6.117ns   193.8mV    111.5mV    402.2mV
20ns      194.3mV    115.5mV    402.3mV
[Rising Waveform]
R_fixture= 50.000
V_fixture= 1.200
V_fixture_min= 1.140
V_fixture_max= 1.260
|time   V(typ)   V(min)   V(max)
0s        873.4mV    977.9mV    684.3mV
895ps     873.4mV    977.9mV    666.9mV
1.233ns   873.5mV    977.9mV    1.174V
1.788ns   851.7mV    977.8mV    1.252V
2.3ns     1.128V     978mV      1.259V
2.938ns   1.192V     978.4mV    1.262V
3.543ns   1.197V     964.2mV    1.263V
4.172ns   1.198V     1.101V     1.263V
4.916ns   1.199V     1.133V     1.263V
20ns      1.2V       1.14V      1.263V
[Falling Waveform]
R_fixture= 50.000
V_fixture= 1.200
V_fixture_min= 1.140
V_fixture_max= 1.260
|time   V(typ)   V(min)   V(max)
0s        1.2V       1.14V      1.263V
1.039ns   1.2V       1.14V      1.287V
1.309ns   1.2V       1.14V      920.4mV
1.496ns   1.2V       1.14V      801.3mV
2.34ns    1.162V     1.14V      699.8mV
2.855ns   930.3mV    1.14V      690.7mV
3.743ns   882.7mV    1.14V      685.5mV
4.583ns   876.8mV    1.145V     684.6mV
6.231ns   874mV      983.9mV    684.3mV
20ns      873.4mV    977.9mV    684.3mV
[Falling Waveform]
R_fixture= 50.000
V_fixture= 0.0
V_fixture_min= 0.0
V_fixture_max= 0.0
|time   V(typ)   V(min)   V(max)
0s        194.3mV    115.5mV    402.3mV
930ps     194.3mV    115.5mV    400.5mV
1.22ns    194.3mV    115.5mV    64.34mV
1.587ns   194.3mV    115.5mV    8.153mV
1.948ns   190.2mV    115.5mV    3.321mV
2.432ns   28.63mV    115.5mV    1.341mV
2.978ns   3.099mV    115.6mV    380.1uV
3.836ns   939uV      115.8mV    93.53uV
5.242ns   193.8uV    2.879mV    14.43uV
20ns      3.523nV    -297.3nV   -626.4nV
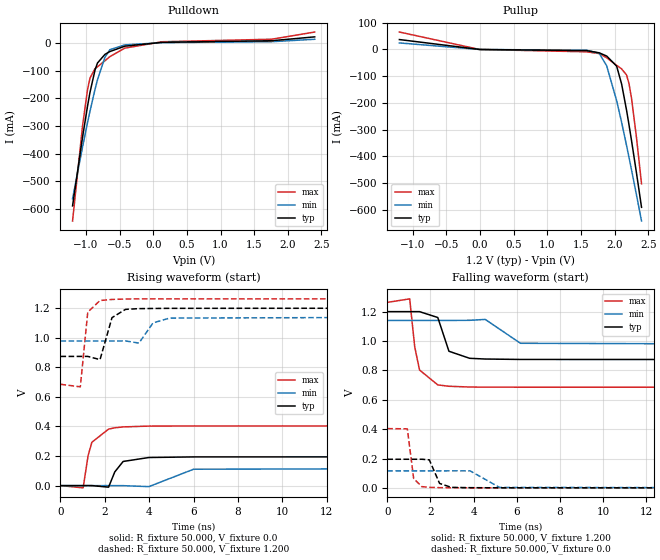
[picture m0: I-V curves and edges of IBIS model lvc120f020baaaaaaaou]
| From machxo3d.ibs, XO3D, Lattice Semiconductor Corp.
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|   Model lvc120f020baaaaaaaou
[Model] lvc120f020baaaaaaaou
Model_type Output
Polarity   Non-Inverting
Enable   Active-High
Vmeas =  0.600V
Cref =  0.0F
Rref =  1.000M
Vref =  0.0V
C_comp   4.200pF   3.800pF   7.500pF
[Temperature Range]   25.000   0.105k   -40.000
[Voltage Range]   1.200V   1.140V   1.260V
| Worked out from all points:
|   slope of the pulldown table from 0 to 0.18 V, typ, clamps not added: 55.1 ohm
|   slope of the pullup table from 0 to 0.18 V, typ, clamps not added: 85 ohm
|   rising waveform, R_fixture 50.000, V_fixture 0.0: 20-80 % time 437ps typ, 571ps min, 397ps max; typ from 0 V to 0.195 V
|   rising waveform, R_fixture 50.000, V_fixture 1.200: 20-80 % time 335ps typ, 482ps min, 207ps max; typ from 0.874 V to 1.2 V
|   falling waveform, R_fixture 50.000, V_fixture 1.200: 20-80 % time 425ps typ, 615ps min, 350ps max; typ from 1.2 V to 0.874 V
|   falling waveform, R_fixture 50.000, V_fixture 0.0: 20-80 % time 335ps typ, 498ps min, 181ps max; typ from 0.195 V to 0 V
[Pulldown]
|Voltage   I(typ)   I(min)   I(max)
-1.2V     -588.5mA   -562.6mA   -643.2mA
-1.052V   -341.1mA   -376.3mA   -300.5mA
-978mV    -229mA     -288.4mA   -169.1mA
-941mV    -178.7mA   -246.5mA   -126.7mA
-867mV    -98.35mA   -168.4mA   -92.95mA
-830mV    -72.39mA   -133.3mA   -85.89mA
-719mV    -41.1mA    -51.67mA   -64.03mA
-645mV    -30.75mA   -23.95mA   -49.04mA
-423mV    -11.34mA   -6.735mA   -18.42mA
132mV     2.529mA    1.315mA    4.626mA
1.76V     8.329mA    4.905mA    13.76mA
2.4V      22.31mA    13.62mA    39.77mA
[Pullup]
|Voltage   I(typ)   I(min)   I(max)
-1.2V     37.21mA    24.58mA    65.39mA
-5mV      72.32uA    46.44uA    -26.55uA
1.586V    -4.324mA   -2.856mA   -8.722mA
1.771V    -12.46mA   -14.55mA   -15.4mA
1.882V    -24.64mA   -61.18mA   -31.08mA
2.03V     -62.24mA   -191.6mA   -59.46mA
2.104V    -129.6mA   -272.9mA   -72.75mA
2.178V    -228.3mA   -360.4mA   -95.81mA
2.215V    -284mA     -405.7mA   -129.1mA
2.252V    -342.3mA   -451.9mA   -183.9mA
2.326V    -464.4mA   -546.1mA   -332.1mA
2.4V      -591.1mA   -642.4mA   -503.3mA
[Ramp]
| variable   typ   min   max
dV/dt_r   0.117/0.399n   69.351m/0.574n   0.242/0.398n
dV/dt_f   0.196/0.434n   97.199m/0.595n   0.345/0.351n
R_load = 50.000
[Rising Waveform]
R_fixture= 50.000
V_fixture= 0.0
V_fixture_min= 0.0
V_fixture_max= 0.0
|time   V(typ)   V(min)   V(max)
0s        284.9uV    165.7uV    490.2uV
1.022ns   312.2uV    179uV      -14.86mV
1.247ns   465.8uV    179uV      203.9mV
1.416ns   349.1uV    179uV      293.3mV
2.169ns   -10.29mV   269.9uV    382.5mV
2.447ns   92.73mV    320.1uV    391.2mV
2.825ns   163.6mV    -49.07uV   397.2mV
3.983ns   190.3mV    -6.577mV   402.7mV
6.001ns   194.3mV    111.1mV    403.6mV
20ns      194.9mV    115.8mV    403.7mV
[Rising Waveform]
R_fixture= 50.000
V_fixture= 1.200
V_fixture_min= 1.140
V_fixture_max= 1.260
|time   V(typ)   V(min)   V(max)
0s        873.8mV    978mV      685.5mV
895ps     873.9mV    978mV      668.2mV
1.231ns   874mV      978mV      1.173V
1.783ns   852.2mV    978mV      1.252V
2.323ns   1.136V     978.2mV    1.259V
2.931ns   1.192V     978.6mV    1.262V
3.536ns   1.197V     963.9mV    1.263V
4.169ns   1.198V     1.1V       1.263V
4.912ns   1.199V     1.133V     1.263V
20ns      1.2V       1.14V      1.263V
[Falling Waveform]
R_fixture= 50.000
V_fixture= 1.200
V_fixture_min= 1.140
V_fixture_max= 1.260
|time   V(typ)   V(min)   V(max)
0s        1.2V       1.14V      1.263V
1.039ns   1.2V       1.14V      1.287V
1.273ns   1.2V       1.14V      959.3mV
1.496ns   1.2V       1.14V      802.6mV
2.342ns   1.16V      1.14V      701mV
2.858ns   930.3mV    1.14V      691.9mV
3.817ns   882.3mV    1.141V     686.7mV
4.542ns   877.4mV    1.147V     685.9mV
6.173ns   874.5mV    984.6mV    685.6mV
20ns      873.8mV    978mV      685.5mV
[Falling Waveform]
R_fixture= 50.000
V_fixture= 0.0
V_fixture_min= 0.0
V_fixture_max= 0.0
|time   V(typ)   V(min)   V(max)
0s        194.9mV    115.8mV    403.7mV
930ps     194.9mV    115.8mV    401.9mV
1.223ns   194.9mV    115.8mV    63.43mV
1.605ns   194.9mV    115.8mV    8.243mV
1.948ns   190.8mV    115.8mV    3.856mV
2.425ns   30.24mV    115.8mV    1.666mV
2.968ns   3.47mV     115.9mV    917.5uV
3.836ns   1.287mV    116.1mV    605.6uV
5.197ns   509.7uV    3.432mV    512uV
20ns      284.7uV    165.3uV    489.2uV
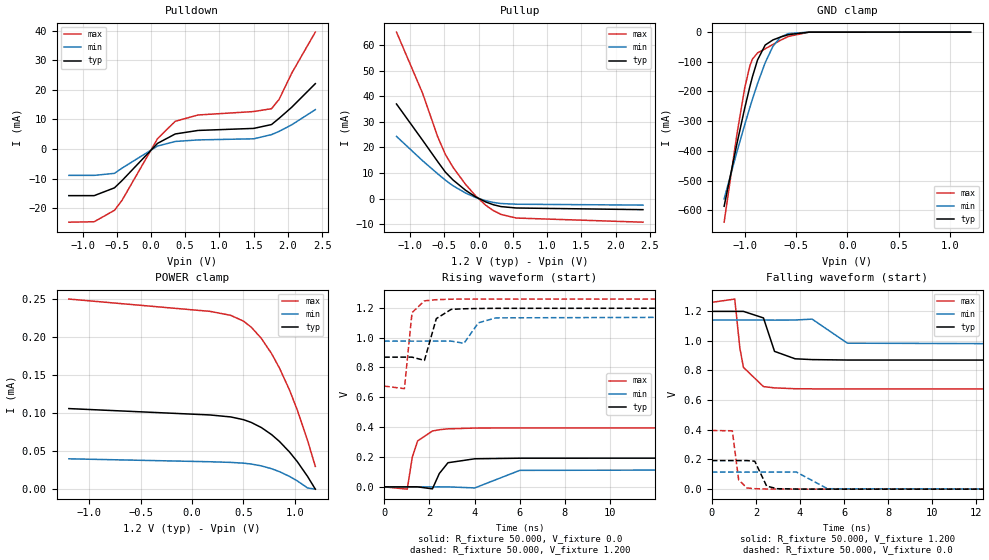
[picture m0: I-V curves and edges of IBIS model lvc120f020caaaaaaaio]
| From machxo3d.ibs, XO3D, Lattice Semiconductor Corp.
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|   Model lvc120f020caaaaaaaio
[Model] lvc120f020caaaaaaaio
Model_type I/O
Polarity   Non-Inverting
Enable   Active-Low
Vinl =  0.420V
Vinh =  0.780V
Vmeas =  0.600V
Cref =  0.0F
Rref =  1.000M
Vref =  0.0V
C_comp   4.200pF   3.800pF   7.500pF
[Temperature Range]   25.000   0.105k   -40.000
[Voltage Range]   1.200V   1.140V   1.260V
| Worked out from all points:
|   slope of the pulldown table from 0 to 0.18 V, typ, clamps not added: 55.1 ohm
|   slope of the pullup table from 0 to 0.18 V, typ, clamps not added: 85.3 ohm
|   GND clamp passes 1 mA (typ) near -0.44 V on its own axis
|   rising waveform, R_fixture 50.000, V_fixture 0.0: 20-80 % time 402ps typ, 577ps min, 389ps max; typ from 0 V to 0.192 V
|   rising waveform, R_fixture 50.000, V_fixture 1.200: 20-80 % time 339ps typ, 489ps min, 207ps max; typ from 0.869 V to 1.2 V
|   falling waveform, R_fixture 50.000, V_fixture 1.200: 20-80 % time 429ps typ, 620ps min, 347ps max; typ from 1.2 V to 0.869 V
|   falling waveform, R_fixture 50.000, V_fixture 0.0: 20-80 % time 333ps typ, 497ps min, 178ps max; typ from 0.192 V to 0 V
[Pulldown]
|Voltage   I(typ)   I(min)   I(max)
-1.2V     -15.77mA   -8.921mA   -24.76mA
-830mV    -15.77mA   -8.921mA   -24.61mA
-534mV    -13.14mA   -8.234mA   -20.74mA
-423mV    -10.67mA   -6.463mA   -17.35mA
95mV      1.91mA     997.3uA    3.496mA
354mV     5.095mA    2.558mA    9.38mA
687mV     6.287mA    3.08mA     11.52mA
1.501V    6.981mA    3.462mA    12.68mA
1.76V     8.277mA    4.874mA    13.65mA
1.871V    10.39mA    5.968mA    16.8mA
2.056V    14.15mA    8.209mA    25.7mA
2.4V      22.12mA    13.32mA    39.57mA
[Pullup]
|Voltage   I(typ)   I(min)   I(max)
-1.2V     37.02mA    24.33mA    65.17mA
-819mV    22.84mA    14.82mA    41.24mA
-597mV    14.42mA    9.661mA    24.11mA
-486mV    10.36mA    7.225mA    17.27mA
-375mV    7.301mA    5.024mA    12.26mA
-190mV    3.229mA    2.154mA    5.518mA
-42mV     628.1uA    407.3uA    979.6uA
106mV     -1.356mA   -861.5uA   -2.669mA
217mV     -2.425mA   -1.522mA   -4.729mA
328mV     -3.145mA   -1.941mA   -6.218mA
550mV     -3.688mA   -2.208mA   -7.621mA
2.4V      -4.336mA   -2.552mA   -9.245mA
[GND_clamp]
|Voltage   I(typ)   I(min)   I(max)
-1.2V     -586.8mA   -561.7mA   -640.4mA
-1.075V   -375.3mA   -403.2mA   -342.9mA
-1V       -256.8mA   -312.4mA   -188.9mA
-950mV    -184.3mA   -254.5mA   -114.1mA
-925mV    -151.1mA   -226.6mA   -91.32mA
-875mV    -94.01mA   -173.6mA   -70.06mA
-800mV    -43.56mA   -102.9mA   -56.11mA
-725mV    -26.45mA   -48.06mA   -41.65mA
-650mV    -16.55mA   -16.39mA   -27.24mA
-575mV    -8.728mA   -5.059mA   -14.79mA
-375mV    -266.5uA   -129.3uA   -404.6uA
1.2V      0A         0A         0A
[POWER_clamp]
|Voltage   I(typ)   I(min)   I(max)
-1.2V     106.1uA    39.97uA    250.3uA
175mV     97.7uA     36.09uA    234.1uA
375mV     95.13uA    35.25uA    228.9uA
500mV     91.53uA    34.24uA    221.3uA
575mV     87.92uA    33.12uA    213.4uA
675mV     81.09uA    30.65uA    198.5uA
775mV     71.72uA    26.88uA    178.3uA
850mV     62.93uA    23.1uA     159.7uA
950mV     48.73uA    16.7uA     130.1uA
1.025V    36.14uA    10.83uA    104uA
1.125V    16.67uA    1.54uA     64.01uA
1.2V      0A         0A         29.9uA
[Ramp]
| variable   typ   min   max
dV/dt_r   0.115/0.425n   68.972m/0.570n   0.237/0.389n
dV/dt_f   0.197/0.431n   97.592m/0.600n   0.348/0.349n
R_load = 50.000
[Rising Waveform]
R_fixture= 50.000
V_fixture= 0.0
V_fixture_min= 0.0
V_fixture_max= 0.0
|time   V(typ)   V(min)   V(max)
0s        4.561nV    56.64nV    2.182nV
1.022ns   1.408uV    15.05uV    -15.49mV
1.243ns   173.8uV    15.05uV    198.7mV
1.481ns   26.46uV    -9.944uV   307.8mV
2.135ns   -13.46mV   64.61uV    374.2mV
2.438ns   88.78mV    162.8uV    382.7mV
2.824ns   161.7mV    -216.7uV   388.6mV
4.011ns   188mV      -7.077mV   393.9mV
5.998ns   191.9mV    110.3mV    394.8mV
20ns      192.4mV    114.9mV    394.9mV
[Rising Waveform]
R_fixture= 50.000
V_fixture= 1.200
V_fixture_min= 1.140
V_fixture_max= 1.260
|time   V(typ)   V(min)   V(max)
0s        868.8mV    976.1mV    675.1mV
895ps     868.9mV    976.2mV    657.8mV
1.233ns   868.9mV    976.1mV    1.167V
1.782ns   847.3mV    976.1mV    1.246V
2.307ns   1.127V     976.2mV    1.254V
2.965ns   1.189V     976.4mV    1.257V
3.53ns    1.193V     961.6mV    1.258V
4.17ns    1.195V     1.099V     1.258V
4.944ns   1.196V     1.132V     1.258V
20ns      1.197V     1.139V     1.258V
[Falling Waveform]
R_fixture= 50.000
V_fixture= 1.200
V_fixture_min= 1.140
V_fixture_max= 1.260
|time   V(typ)   V(min)   V(max)
0s        1.197V     1.139V     1.258V
1.04ns    1.197V     1.139V     1.28V
1.273ns   1.197V     1.139V     949.2mV
1.434ns   1.197V     1.139V     820.2mV
2.342ns   1.153V     1.139V     690.5mV
2.844ns   927.8mV    1.138V     682mV
3.78ns    877.8mV    1.139V     676.3mV
4.549ns   872.4mV    1.145V     675.4mV
6.148ns   869.5mV    983mV      675.1mV
20ns      868.8mV    976.1mV    675.1mV
[Falling Waveform]
R_fixture= 50.000
V_fixture= 0.0
V_fixture_min= 0.0
V_fixture_max= 0.0
|time   V(typ)   V(min)   V(max)
0s        192.4mV    114.9mV    394.9mV
930ps     192.4mV    115mV      393.1mV
1.217ns   192.4mV    115mV      63.16mV
1.591ns   192.4mV    115mV      7.774mV
1.948ns   188.3mV    115mV      3.41mV
2.487ns   20.55mV    115mV      983.8uV
2.958ns   3.228mV    115.1mV    402.8uV
3.837ns   839.5uV    115.3mV    105.4uV
5.247ns   153.1uV    2.875mV    18.68uV
20ns      -146.5nV   -298.5nV   -105.9nV
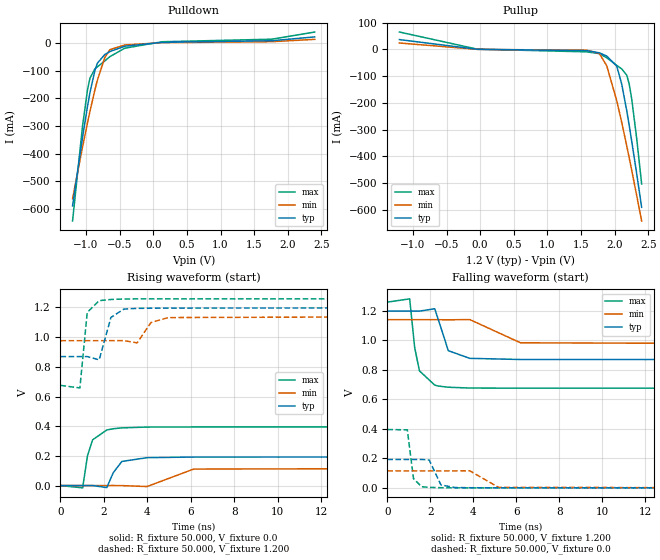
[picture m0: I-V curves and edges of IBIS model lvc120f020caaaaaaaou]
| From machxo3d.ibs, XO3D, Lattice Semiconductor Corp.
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|   Model lvc120f020caaaaaaaou
[Model] lvc120f020caaaaaaaou
Model_type Output
Polarity   Non-Inverting
Enable   Active-High
Vmeas =  0.600V
Cref =  0.0F
Rref =  1.000M
Vref =  0.0V
C_comp   4.200pF   3.800pF   7.500pF
[Temperature Range]   25.000   0.105k   -40.000
[Voltage Range]   1.200V   1.140V   1.260V
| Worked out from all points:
|   slope of the pulldown table from 0 to 0.18 V, typ, clamps not added: 54.5 ohm
|   slope of the pullup table from 0 to 0.18 V, typ, clamps not added: 85.2 ohm
|   rising waveform, R_fixture 50.000, V_fixture 0.0: 20-80 % time 434ps typ, 568ps min, 383ps max; typ from 0 V to 0.192 V
|   rising waveform, R_fixture 50.000, V_fixture 1.200: 20-80 % time 340ps typ, 497ps min, 206ps max; typ from 0.869 V to 1.2 V
|   falling waveform, R_fixture 50.000, V_fixture 1.200: 20-80 % time 427ps typ, 614ps min, 345ps max; typ from 1.2 V to 0.869 V
|   falling waveform, R_fixture 50.000, V_fixture 0.0: 20-80 % time 330ps typ, 497ps min, 178ps max; typ from 0.192 V to 0 V
[Pulldown]
|Voltage   I(typ)   I(min)   I(max)
-1.2V     -588.5mA   -562.6mA   -643.3mA
-1.052V   -341.1mA   -376.3mA   -300.6mA
-978mV    -229mA     -288.4mA   -169.2mA
-941mV    -178.7mA   -246.5mA   -126.7mA
-867mV    -98.4mA    -168.4mA   -93mA
-830mV    -72.44mA   -133.3mA   -85.94mA
-719mV    -41.14mA   -51.7mA    -64.09mA
-645mV    -30.8mA    -23.97mA   -49.11mA
-423mV    -11.42mA   -6.781mA   -18.53mA
132mV     2.569mA    1.333mA    4.719mA
1.76V     8.38mA     4.913mA    13.89mA
2.4V      22.23mA    13.36mA    39.82mA
[Pullup]
|Voltage   I(typ)   I(min)   I(max)
-1.2V     37.12mA    24.37mA    65.42mA
-42mV     727.4uA    444uA      1.217mA
1.586V    -4.396mA   -2.904mA   -8.825mA
1.771V    -12.51mA   -14.58mA   -15.48mA
1.882V    -24.68mA   -61.2mA    -31.14mA
2.03V     -62.29mA   -191.6mA   -59.5mA
2.104V    -129.7mA   -273mA     -72.8mA
2.178V    -228.4mA   -360.4mA   -95.85mA
2.215V    -284.1mA   -405.7mA   -129.1mA
2.252V    -342.4mA   -451.9mA   -184mA
2.326V    -464.4mA   -546.1mA   -332.2mA
2.4V      -591.1mA   -642.4mA   -503.3mA
[Ramp]
| variable   typ   min   max
dV/dt_r   0.115/0.423n   68.972m/0.569n   0.237/0.385n
dV/dt_f   0.197/0.430n   97.592m/0.600n   0.348/0.348n
R_load = 50.000
[Rising Waveform]
R_fixture= 50.000
V_fixture= 0.0
V_fixture_min= 0.0
V_fixture_max= 0.0
|time   V(typ)   V(min)   V(max)
0s        4.535nV    56.85nV    2.146nV
1.022ns   14.96uV    13.7uV     -15.52mV
1.245ns   187.4uV    13.7uV     200.6mV
1.479ns   75.06uV    13.7uV     308mV
2.132ns   -13.67mV   63.89uV    374.3mV
2.432ns   86.71mV    166.4uV    382.8mV
2.827ns   162.3mV    -217.7uV   388.7mV
3.982ns   187.8mV    -6.8mV     394mV
6.133ns   192mV      111.1mV    394.8mV
20ns      192.4mV    114.9mV    394.9mV
[Rising Waveform]
R_fixture= 50.000
V_fixture= 1.200
V_fixture_min= 1.140
V_fixture_max= 1.260
|time   V(typ)   V(min)   V(max)
0s        868.8mV    976.1mV    675.1mV
895ps     868.9mV    976.1mV    657.8mV
1.233ns   869mV      976.1mV    1.167V
1.783ns   847.3mV    976.1mV    1.246V
2.325ns   1.133V     976.4mV    1.254V
2.918ns   1.189V     976.7mV    1.257V
3.53ns    1.194V     961.6mV    1.258V
4.169ns   1.195V     1.099V     1.258V
4.965ns   1.196V     1.132V     1.258V
20ns      1.197V     1.139V     1.258V
[Falling Waveform]
R_fixture= 50.000
V_fixture= 1.200
V_fixture_min= 1.140
V_fixture_max= 1.260
|time   V(typ)   V(min)   V(max)
0s        1.197V     1.139V     1.258V
1.04ns    1.197V     1.139V     1.28V
1.273ns   1.197V     1.139V     949.1mV
1.495ns   1.197V     1.139V     792mV
2.206ns   1.213V     1.139V     695.8mV
2.362ns   1.144V     1.139V     689.7mV
2.836ns   929mV      1.138V     681.5mV
3.832ns   877.1mV    1.14V      676mV
6.195ns   869.4mV    982.4mV    675.1mV
20ns      868.8mV    976.1mV    675.1mV
[Falling Waveform]
R_fixture= 50.000
V_fixture= 0.0
V_fixture_min= 0.0
V_fixture_max= 0.0
|time   V(typ)   V(min)   V(max)
0s        192.4mV    114.9mV    394.9mV
930ps     192.4mV    115mV      393.1mV
1.218ns   192.4mV    115mV      62.13mV
1.597ns   192.4mV    115mV      7.491mV
1.948ns   188.3mV    115mV      3.195mV
2.493ns   19.62mV    114.9mV    1.073mV
3.136ns   2.182mV    114.9mV    250.5uV
3.836ns   856.1uV    115.3mV    87.2uV
5.174ns   236.1uV    3.405mV    39.5uV
20ns      -125.2nV   -292.4nV   -375.9nV
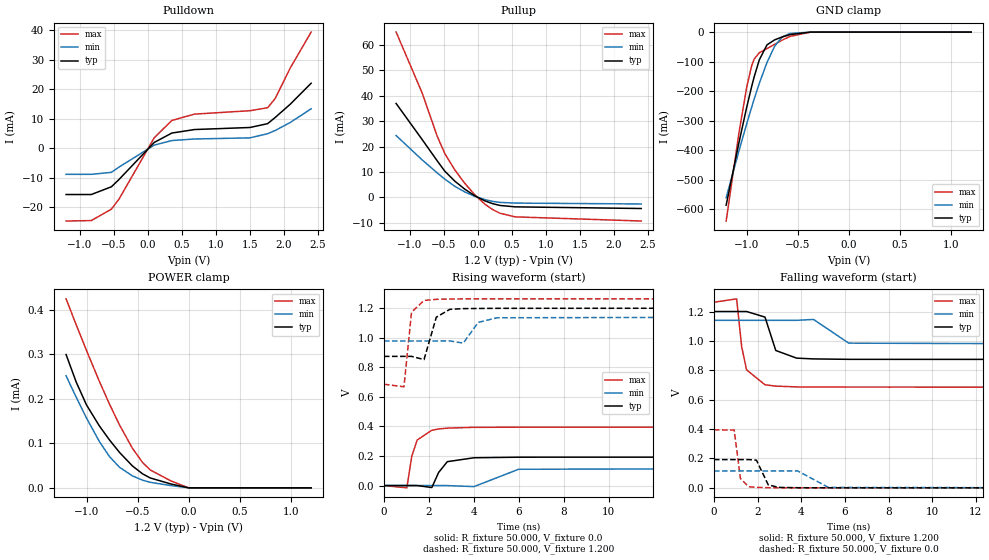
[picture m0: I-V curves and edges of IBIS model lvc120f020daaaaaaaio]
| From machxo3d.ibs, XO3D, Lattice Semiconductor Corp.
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|   Model lvc120f020daaaaaaaio
[Model] lvc120f020daaaaaaaio
Model_type I/O
Polarity   Non-Inverting
Enable   Active-Low
Vinl =  0.420V
Vinh =  0.780V
Vmeas =  0.600V
Cref =  0.0F
Rref =  1.000M
Vref =  0.0V
C_comp   4.200pF   3.800pF   7.500pF
[Temperature Range]   25.000   0.105k   -40.000
[Voltage Range]   1.200V   1.140V   1.260V
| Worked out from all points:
|   slope of the pulldown table from 0 to 0.18 V, typ, clamps not added: 55.1 ohm
|   slope of the pullup table from 0 to 0.18 V, typ, clamps not added: 85.3 ohm
|   GND clamp passes 1 mA (typ) near -0.44 V on its own axis
|   rising waveform, R_fixture 50.000, V_fixture 0.0: 20-80 % time 402ps typ, 577ps min, 389ps max; typ from 0 V to 0.192 V
|   rising waveform, R_fixture 50.000, V_fixture 1.200: 20-80 % time 336ps typ, 484ps min, 206ps max; typ from 0.874 V to 1.2 V
|   falling waveform, R_fixture 50.000, V_fixture 1.200: 20-80 % time 432ps typ, 619ps min, 351ps max; typ from 1.2 V to 0.874 V
|   falling waveform, R_fixture 50.000, V_fixture 0.0: 20-80 % time 333ps typ, 497ps min, 178ps max; typ from 0.192 V to 0 V
[Pulldown]
|Voltage   I(typ)   I(min)   I(max)
-1.2V     -15.77mA   -8.921mA   -24.76mA
-830mV    -15.77mA   -8.921mA   -24.61mA
-534mV    -13.14mA   -8.234mA   -20.74mA
-423mV    -10.67mA   -6.463mA   -17.35mA
95mV      1.91mA     997.3uA    3.496mA
354mV     5.095mA    2.558mA    9.38mA
687mV     6.287mA    3.08mA     11.52mA
1.501V    6.983mA    3.463mA    12.68mA
1.76V     8.276mA    4.869mA    13.69mA
1.871V    10.37mA    5.955mA    16.78mA
2.093V    14.88mA    8.68mA     27.18mA
2.4V      22.01mA    13.33mA    39.38mA
[Pullup]
|Voltage   I(typ)   I(min)   I(max)
-1.2V     36.91mA    24.32mA    64.96mA
-819mV    22.8mA     14.8mA     41.13mA
-597mV    14.41mA    9.656mA    24.1mA
-486mV    10.37mA    7.225mA    17.3mA
-338mV    6.412mA    4.38mA     10.82mA
-190mV    3.229mA    2.154mA    5.518mA
-42mV     628.1uA    407.3uA    979.6uA
106mV     -1.356mA   -861.5uA   -2.669mA
217mV     -2.425mA   -1.522mA   -4.729mA
328mV     -3.145mA   -1.941mA   -6.218mA
550mV     -3.688mA   -2.208mA   -7.621mA
2.4V      -4.336mA   -2.552mA   -9.245mA
[GND_clamp]
|Voltage   I(typ)   I(min)   I(max)
-1.2V     -586.8mA   -561.7mA   -640.4mA
-1.075V   -375.3mA   -403.2mA   -342.9mA
-1V       -256.8mA   -312.4mA   -188.9mA
-950mV    -184.3mA   -254.5mA   -114.1mA
-925mV    -151.1mA   -226.6mA   -91.32mA
-875mV    -94.01mA   -173.6mA   -70.06mA
-800mV    -43.56mA   -102.9mA   -56.11mA
-725mV    -26.45mA   -48.06mA   -41.65mA
-650mV    -16.55mA   -16.39mA   -27.24mA
-575mV    -8.728mA   -5.059mA   -14.79mA
-375mV    -266.5uA   -129.3uA   -404.6uA
1.2V      -42.59nA   0A         -5.33uA
[POWER_clamp]
|Voltage   I(typ)   I(min)   I(max)
-1.2V     299.6uA    251.9uA    424.8uA
-1.1V     237.3uA    203.2uA    366uA
-1V       186.4uA    156.9uA    308.7uA
-875mV    139.5uA    104.5uA    239.9uA
-775mV    107.7uA    70.18uA    188.3uA
-675mV    79.18uA    45.9uA     140.6uA
-550mV    49.19uA    26.84uA    88.83uA
-450mV    31.3uA     17.16uA    56.66uA
-375mV    22.16uA    12.38uA    40.11uA
-175mV    8.775uA    5.159uA    15.8uA
0V        3.648nA    7.36nA     0A
1.2V      0A         0A         0A
[Ramp]
| variable   typ   min   max
dV/dt_r   0.115/0.425n   68.972m/0.570n   0.237/0.389n
dV/dt_f   0.196/0.434n   97.199m/0.595n   0.345/0.352n
R_load = 50.000
[Rising Waveform]
R_fixture= 50.000
V_fixture= 0.0
V_fixture_min= 0.0
V_fixture_max= 0.0
|time   V(typ)   V(min)   V(max)
0s        4.561nV    56.64nV    2.182nV
1.022ns   1.709uV    15.02uV    -15.49mV
1.243ns   174.9uV    15.02uV    198.7mV
1.481ns   54.4uV     -9.944uV   307.8mV
2.135ns   -13.46mV   64.61uV    374.2mV
2.438ns   88.78mV    162.8uV    382.7mV
2.824ns   161.7mV    -216.7uV   388.6mV
4.011ns   188mV      -7.077mV   393.9mV
5.998ns   191.9mV    110.3mV    394.8mV
20ns      192.4mV    114.9mV    394.9mV
[Rising Waveform]
R_fixture= 50.000
V_fixture= 1.200
V_fixture_min= 1.140
V_fixture_max= 1.260
|time   V(typ)   V(min)   V(max)
0s        873.8mV    978mV      685.5mV
895ps     873.9mV    978mV      668.2mV
1.231ns   874mV      978mV      1.173V
1.787ns   852.2mV    978mV      1.252V
2.334ns   1.139V     978.2mV    1.26V
2.932ns   1.192V     978.6mV    1.262V
3.532ns   1.197V     963.6mV    1.263V
4.202ns   1.198V     1.104V     1.263V
5.034ns   1.199V     1.135V     1.263V
20ns      1.2V       1.14V      1.263V
[Falling Waveform]
R_fixture= 50.000
V_fixture= 1.200
V_fixture_min= 1.140
V_fixture_max= 1.260
|time   V(typ)   V(min)   V(max)
0s        1.2V       1.14V      1.263V
1.041ns   1.2V       1.14V      1.286V
1.273ns   1.2V       1.14V      959.4mV
1.496ns   1.2V       1.14V      803mV
2.34ns    1.162V     1.14V      701.4mV
2.834ns   934.8mV    1.14V      692.2mV
3.787ns   882.7mV    1.14V      686.9mV
4.564ns   877.4mV    1.146V     685.9mV
6.174ns   874.5mV    984.7mV    685.6mV
20ns      873.8mV    978mV      685.5mV
[Falling Waveform]
R_fixture= 50.000
V_fixture= 0.0
V_fixture_min= 0.0
V_fixture_max= 0.0
|time   V(typ)   V(min)   V(max)
0s        192.4mV    114.9mV    394.9mV
930ps     192.4mV    115mV      393.1mV
1.217ns   192.4mV    115mV      63.16mV
1.591ns   192.4mV    115mV      7.774mV
1.948ns   188.3mV    115mV      3.41mV
2.491ns   20.1mV     114.9mV    983.8uV
2.977ns   3.084mV    115.1mV    402.8uV
3.837ns   932.3uV    115.3mV    105.4uV
5.247ns   193.1uV    2.875mV    18.68uV
20ns      -146.6nV   -298.5nV   -105.9nV
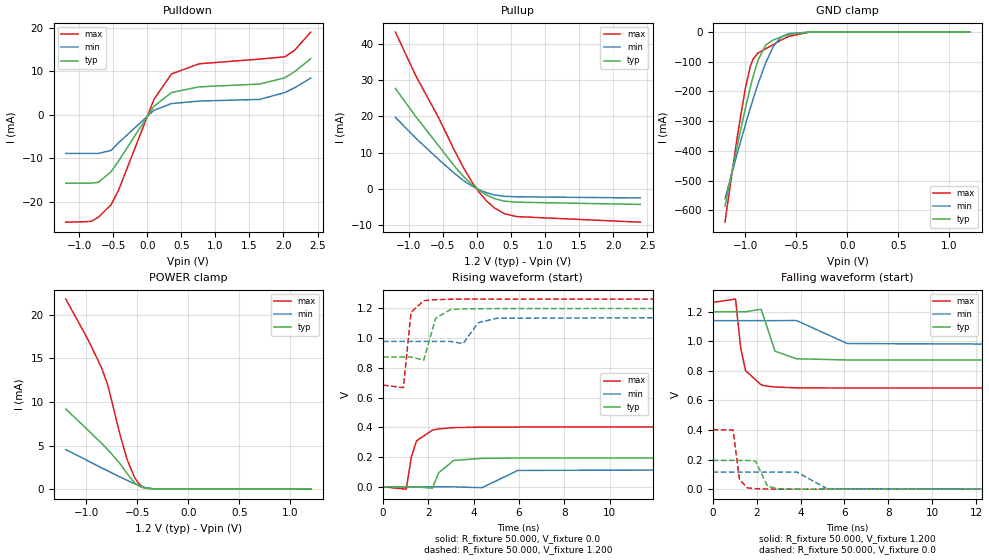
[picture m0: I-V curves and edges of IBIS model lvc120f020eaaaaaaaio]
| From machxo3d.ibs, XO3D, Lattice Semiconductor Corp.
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|   Model lvc120f020eaaaaaaaio
[Model] lvc120f020eaaaaaaaio
Model_type I/O
Polarity   Non-Inverting
Enable   Active-Low
Vinl =  0.420V
Vinh =  0.780V
Vmeas =  0.600V
Cref =  0.0F
Rref =  1.000M
Vref =  0.0V
C_comp   4.200pF   3.800pF   7.500pF
[Temperature Range]   25.000   0.105k   -40.000
[Voltage Range]   1.200V   1.140V   1.260V
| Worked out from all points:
|   slope of the pulldown table from 0 to 0.18 V, typ, clamps not added: 55.1 ohm
|   slope of the pullup table from 0 to 0.18 V, typ, clamps not added: 85.3 ohm
|   GND clamp passes 1 mA (typ) near -0.44 V on its own axis
|   POWER clamp passes 1 mA (typ) near -0.55 V on its own axis
|   rising waveform, R_fixture 50.000, V_fixture 0.0: 20-80 % time 406ps typ, 579ps min, 397ps max; typ from 0 V to 0.194 V
|   rising waveform, R_fixture 50.000, V_fixture 1.200: 20-80 % time 337ps typ, 492ps min, 207ps max; typ from 0.873 V to 1.2 V
|   falling waveform, R_fixture 50.000, V_fixture 1.200: 20-80 % time 432ps typ, 618ps min, 349ps max; typ from 1.2 V to 0.873 V
|   falling waveform, R_fixture 50.000, V_fixture 0.0: 20-80 % time 333ps typ, 500ps min, 181ps max; typ from 0.194 V to 0 V
[Pulldown]
|Voltage   I(typ)   I(min)   I(max)
-1.2V     -15.77mA   -8.921mA   -24.76mA
-830mV    -15.77mA   -8.921mA   -24.61mA
-719mV    -15.58mA   -8.921mA   -23.61mA
-534mV    -13.14mA   -8.234mA   -20.74mA
-423mV    -10.67mA   -6.463mA   -17.35mA
95mV      1.91mA     997.3uA    3.496mA
354mV     5.095mA    2.558mA    9.38mA
761mV     6.397mA    3.131mA    11.71mA
1.649V    7.049mA    3.505mA    12.79mA
2.019V    8.479mA    5.088mA    13.33mA
2.167V    9.932mA    6.227mA    14.87mA
2.4V      12.88mA    8.418mA    19.01mA
[Pullup]
|Voltage   I(typ)   I(min)   I(max)
-1.2V     27.77mA    19.76mA    43.33mA
-893mV    19.78mA    13.89mA    31.01mA
-560mV    11.8mA     8.039mA    19.5mA
-338mV    6.396mA    4.353mA    10.82mA
-190mV    3.229mA    2.154mA    5.518mA
-79mV     1.223mA    799.3uA    2.039mA
32mV      -444uA     -284.1uA   -972.5uA
143mV     -1.752mA   -1.109mA   -3.419mA
254mV     -2.703mA   -1.688mA   -5.288mA
402mV     -3.439mA   -2.096mA   -6.902mA
587mV     -3.713mA   -2.22mA    -7.705mA
2.4V      -4.336mA   -2.552mA   -9.246mA
[GND_clamp]
|Voltage   I(typ)   I(min)   I(max)
-1.2V     -586.8mA   -561.6mA   -640.3mA
-1.075V   -375.3mA   -403.2mA   -342.9mA
-1V       -256.8mA   -312.3mA   -188.8mA
-950mV    -184.3mA   -254.5mA   -114.1mA
-925mV    -151.1mA   -226.6mA   -91.26mA
-875mV    -93.95mA   -173.6mA   -69.99mA
-800mV    -43.5mA    -102.9mA   -56.04mA
-725mV    -26.4mA    -48.03mA   -41.57mA
-650mV    -16.5mA    -16.35mA   -27.16mA
-575mV    -8.667mA   -5.012mA   -14.69mA
-375mV    -183.5uA   -82.46uA   -270.8uA
1.2V      0A         0A         0A
[POWER_clamp]
|Voltage   I(typ)   I(min)   I(max)
-1.2V     9.182mA    4.531mA    21.77mA
-975mV    6.68mA     3.195mA    16.97mA
-850mV    5.256mA    2.452mA    13.9mA
-800mV    4.662mA    2.159mA    12.31mA
-775mV    4.355mA    2.014mA    11.32mA
-675mV    3.015mA    1.438mA    6.52mA
-600mV    1.813mA    1.015mA    3.43mA
-525mV    717.6uA    612.9uA    1.296mA
-475mV    302.2uA    372.2uA    507.9uA
-425mV    111uA      180.2uA    159.4uA
-325mV    13.15uA    20.51uA    12.23uA
1.2V      0A         0A         3.808nA
[Ramp]
| variable   typ   min   max
dV/dt_r   0.117/0.430n   69.294m/0.574n   0.241/0.402n
dV/dt_f   0.196/0.434n   97.283m/0.595n   0.346/0.351n
R_load = 50.000
[Rising Waveform]
R_fixture= 50.000
V_fixture= 0.0
V_fixture_min= 0.0
V_fixture_max= 0.0
|time   V(typ)   V(min)   V(max)
0s        4.736nV    57.27nV    2.383nV
1.021ns   1.271uV    15.12uV    -15.74mV
1.244ns   174.3uV    15.12uV    200mV
1.476ns   51.99uV    -9.839uV   309.5mV
2.177ns   -9.564mV   64.72uV    381.1mV
2.454ns   94.49mV    163.3uV    389.7mV
3.119ns   177.9mV    -286uV     398.3mV
4.369ns   191.3mV    -5.829mV   401.6mV
5.949ns   193.7mV    110.4mV    402.2mV
20ns      194.3mV    115.5mV    402.3mV
[Rising Waveform]
R_fixture= 50.000
V_fixture= 1.200
V_fixture_min= 1.140
V_fixture_max= 1.260
|time   V(typ)   V(min)   V(max)
0s        873.4mV    977.9mV    684.3mV
895ps     873.4mV    977.9mV    666.9mV
1.233ns   873.5mV    977.9mV    1.174V
1.794ns   851.7mV    977.8mV    1.252V
2.318ns   1.134V     978.1mV    1.259V
2.964ns   1.192V     978mV      1.262V
3.53ns    1.197V     963.3mV    1.263V
4.202ns   1.198V     1.104V     1.263V
5.027ns   1.199V     1.134V     1.263V
20ns      1.2V       1.14V      1.263V
[Falling Waveform]
R_fixture= 50.000
V_fixture= 1.200
V_fixture_min= 1.140
V_fixture_max= 1.260
|time   V(typ)   V(min)   V(max)
0s        1.2V       1.14V      1.263V
1.041ns   1.2V       1.14V      1.286V
1.273ns   1.2V       1.14V      958.7mV
1.496ns   1.2V       1.14V      801.8mV
2.204ns   1.217V     1.14V      705.6mV
2.361ns   1.149V     1.14V      699.4mV
2.838ns   933.5mV    1.14V      690.9mV
3.812ns   882mV      1.141V     685.4mV
6.136ns   874.1mV    984.9mV    684.3mV
20ns      873.4mV    977.9mV    684.3mV
[Falling Waveform]
R_fixture= 50.000
V_fixture= 0.0
V_fixture_min= 0.0
V_fixture_max= 0.0
|time   V(typ)   V(min)   V(max)
0s        194.3mV    115.5mV    402.3mV
930ps     194.3mV    115.5mV    400.5mV
1.221ns   194.3mV    115.5mV    64.26mV
1.595ns   194.3mV    115.5mV    8.163mV
1.952ns   189.5mV    115.5mV    3.306mV
2.497ns   20.1mV     115.4mV    1.14mV
3.005ns   3.005mV    115.6mV    346.4uV
3.837ns   872.4uV    115.8mV    78.28uV
5.206ns   167.8uV    3.261mV    34.1uV
20ns      -183.3nV   -307.1nV   -123.9nV
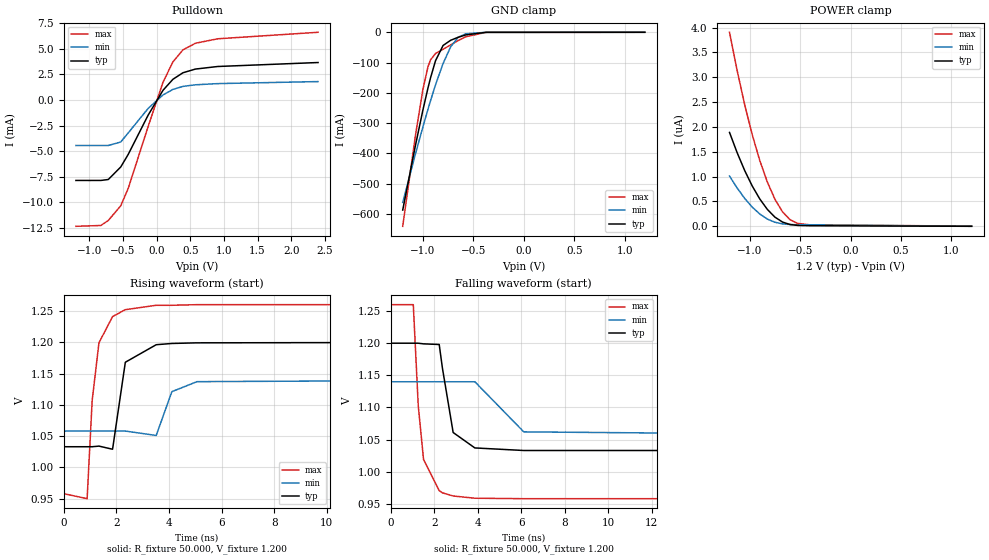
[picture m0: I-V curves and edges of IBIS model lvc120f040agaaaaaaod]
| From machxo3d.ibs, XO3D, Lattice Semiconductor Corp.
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|   Model lvc120f040agaaaaaaod
[Model] lvc120f040agaaaaaaod
Model_type I/O_open_drain
Polarity   Non-Inverting
Enable   Active-Low
Vinl =  0.420V
Vinh =  0.780V
Vmeas =  0.600V
Cref =  0.0F
Rref = 10.00k
Vref = 1.20V
C_comp   4.200pF   3.800pF   7.500pF
[Temperature Range]   25.000   0.105k   -40.000
[Voltage Range]   1.200V   1.140V   1.260V
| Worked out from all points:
|   slope of the pulldown table from 0 to 0.18 V, typ, clamps not added: 110 ohm
|   GND clamp passes 1 mA (typ) near -0.44 V on its own axis
|   rising waveform, R_fixture 50.000, V_fixture 1.200: 20-80 % time 361ps typ, 414ps min, 354ps max; typ from 1.03 V to 1.2 V
|   falling waveform, R_fixture 50.000, V_fixture 1.200: 20-80 % time 447ps typ, 618ps min, 374ps max; typ from 1.2 V to 1.03 V
[Pulldown]
|Voltage   I(typ)   I(min)   I(max)
-1.2V     -7.886mA   -4.461mA   -12.38mA
-830mV    -7.886mA   -4.461mA   -12.3mA
-719mV    -7.792mA   -4.461mA   -11.81mA
-534mV    -6.568mA   -4.117mA   -10.37mA
-423mV    -5.336mA   -3.232mA   -8.675mA
-127mV    -1.491mA   -829.4uA   -2.61mA
95mV      954.9uA    498.6uA    1.748mA
243mV     2.035mA    1.04mA     3.742mA
391mV     2.669mA    1.333mA    4.912mA
576mV     3.031mA    1.49mA     5.562mA
909mV     3.284mA    1.606mA    6mA
2.4V      3.673mA    1.806mA    6.637mA
[GND_clamp]
|Voltage   I(typ)   I(min)   I(max)
-1.2V     -586.8mA   -561.6mA   -640.4mA
-1.075V   -375.3mA   -403.2mA   -342.9mA
-1V       -256.8mA   -312.3mA   -188.8mA
-950mV    -184.3mA   -254.5mA   -114.1mA
-925mV    -151.1mA   -226.6mA   -91.28mA
-875mV    -93.98mA   -173.6mA   -70.02mA
-800mV    -43.52mA   -102.9mA   -56.06mA
-725mV    -26.41mA   -48.03mA   -41.59mA
-650mV    -16.51mA   -16.35mA   -27.18mA
-575mV    -8.675mA   -5.014mA   -14.71mA
-375mV    -184.4uA   -82.53uA   -274.8uA
1.2V      0A         0A         0A
[POWER_clamp]
|Voltage   I(typ)   I(min)   I(max)
-1.2V     1.889uA    1.011uA    3.905uA
-1.125V   1.485uA    772.5nA    3.141uA
-1.05V    1.124uA    563.1nA    2.451uA
-975mV    812.1nA    387.4nA    1.845uA
-900mV    550.1nA    247.6nA    1.324uA
-825mV    340.1nA    145.7nA    890.5nA
-750mV    184.9nA    81.63nA    545.5nA
-675mV    85.57nA    49.1nA     292.2nA
-600mV    35.85nA    35.98nA    132.8nA
-525mV    17.85nA    31.28nA    57.79nA
-400mV    11.64nA    28.62nA    28.94nA
1.2V      0A         0A         3.813nA
[Ramp]
| variable   typ   min   max
dV/dt_r   0.100/0.362n   49.133m/0.416n   0.181/0.357n
dV/dt_f   0.100/0.445n   49.133m/0.609n   0.181/0.381n
R_load = 50.000
[Rising Waveform]
R_fixture= 50.000
V_fixture= 1.200
V_fixture_min= 1.140
V_fixture_max= 1.260
|time   V(typ)   V(min)   V(max)
0s        1.033V     1.058V     958mV
886ps     1.033V     1.058V     950mV
1.078ns   1.033V     1.058V     1.107V
1.335ns   1.034V     1.058V     1.199V
1.853ns   1.029V     1.058V     1.241V
2.338ns   1.168V     1.058V     1.252V
3.511ns   1.196V     1.051V     1.259V
4.107ns   1.198V     1.121V     1.259V
5.062ns   1.199V     1.137V     1.26V
20ns      1.2V       1.14V      1.26V
[Falling Waveform]
R_fixture= 50.000
V_fixture= 1.200
V_fixture_min= 1.140
V_fixture_max= 1.260
|time   V(typ)   V(min)   V(max)
0s        1.2V       1.14V      1.26V
1.042ns   1.2V       1.14V      1.26V
1.27ns    1.2V       1.14V      1.103V
1.513ns   1.199V     1.14V      1.019V
2.233ns   1.198V     1.14V      970.6mV
2.382ns   1.161V     1.14V      967.1mV
2.874ns   1.061V     1.14V      962.2mV
3.871ns   1.037V     1.14V      958.7mV
6.12ns    1.033V     1.062V     958mV
20ns      1.033V     1.058V     958mV
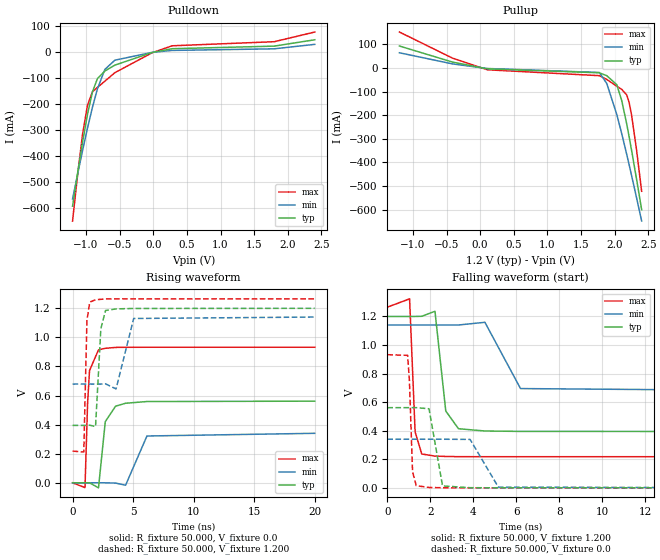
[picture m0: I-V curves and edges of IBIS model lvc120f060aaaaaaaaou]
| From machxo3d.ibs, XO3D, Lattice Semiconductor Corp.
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|   Model lvc120f060aaaaaaaaou
[Model] lvc120f060aaaaaaaaou
Model_type Output
Polarity   Non-Inverting
Enable   Active-High
Vmeas =  0.600V
Cref =  0.0F
Rref =  1.000M
Vref =  0.0V
C_comp   4.200pF   3.800pF   7.500pF
[Temperature Range]   25.000   0.105k   -40.000
[Voltage Range]   1.200V   1.140V   1.260V
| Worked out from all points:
|   slope of the pulldown table from 0 to 0.18 V, typ, clamps not added: 18.4 ohm
|   slope of the pullup table from 0 to 0.18 V, typ, clamps not added: 28.4 ohm
|   rising waveform, R_fixture 50.000, V_fixture 0.0: 20-80 % time 451ps typ, 631ps min, 245ps max; typ from 0 V to 0.561 V
|   rising waveform, R_fixture 50.000, V_fixture 1.200: 20-80 % time 302ps typ, 479ps min, 141ps max; typ from 0.395 V to 1.2 V
|   falling waveform, R_fixture 50.000, V_fixture 1.200: 20-80 % time 344ps typ, 590ps min, 160ps max; typ from 1.2 V to 0.395 V
|   falling waveform, R_fixture 50.000, V_fixture 0.0: 20-80 % time 281ps typ, 499ps min, 120ps max; typ from 0.561 V to 0 V
[Pulldown]
|Voltage   I(typ)   I(min)   I(max)
-1.2V     -591.8mA   -564.5mA   -649mA
-1.126V   -466.6mA   -470.4mA   -473.7mA
-1.052V   -347.3mA   -379.1mA   -316.6mA
-978mV    -238.8mA   -292mA     -203.7mA
-904mV    -152.5mA   -211.3mA   -152.2mA
-830mV    -101.2mA   -140.6mA   -135.1mA
-719mV    -72.26mA   -65.9mA    -111.2mA
-571mV    -49.64mA   -30.71mA   -78.72mA
-16mV     -1.08mA    -574.4uA   -1.961mA
280mV     13.4mA     6.806mA    24.65mA
1.797V    23.32mA    12.96mA    40.33mA
2.4V      47.8mA     30.14mA    77.52mA
[Pullup]
|Voltage   I(typ)   I(min)   I(max)
-1.2V     92.48mA    63.86mA    151.6mA
-412mV    24.6mA     16.87mA    41.32mA
106mV     -4.067mA   -2.584mA   -8.006mA
1.771V    -20.72mA   -19.46mA   -32.89mA
1.882V    -33.01mA   -66.15mA   -48.76mA
2.03V     -70.74mA   -196.6mA   -77.4mA
2.104V    -138.2mA   -278mA     -90.83mA
2.178V    -236.9mA   -365.4mA   -114mA
2.215V    -292.6mA   -410.8mA   -147.3mA
2.252V    -350.9mA   -456.9mA   -202.2mA
2.326V    -473mA     -551.2mA   -350.5mA
2.4V      -599.8mA   -647.5mA   -521.7mA
[Ramp]
| variable   typ   min   max
dV/dt_r   0.337/0.469n   0.204/0.622n   0.559/0.254n
dV/dt_f   0.483/0.344n   0.277/0.595n   0.628/0.160n
R_load = 50.000
[Rising Waveform]
R_fixture= 50.000
V_fixture= 0.0
V_fixture_min= 0.0
V_fixture_max= 0.0
|time   V(typ)   V(min)   V(max)
0s        2.29nV     33nV       1nV
1.027ns   20.68uV    5.828uV    -33.43mV
1.242ns   85.89uV    5.828uV    548.8mV
1.402ns   -122.3uV   5.828uV    772.2mV
2.142ns   -34.95mV   30.65uV    914mV
2.702ns   420.4mV    -249.7uV   925mV
3.553ns   526.7mV    -2.113mV   931mV
4.377ns   547mV      -17mV      931.9mV
6.143ns   558.8mV    321.7mV    932.2mV
20ns      561.3mV    340.2mV    932.2mV
[Rising Waveform]
R_fixture= 50.000
V_fixture= 1.200
V_fixture_min= 1.140
V_fixture_max= 1.260
|time   V(typ)   V(min)   V(max)
0s        394.7mV    678.9mV    217.9mV
929ps     394.7mV    678.9mV    211.4mV
1.186ns   394.5mV    678.9mV    1.115V
1.424ns   395.8mV    678.9mV    1.243V
1.898ns   386.6mV    678.8mV    1.259V
2.336ns   1.06V      678.8mV    1.262V
2.724ns   1.185V     680.4mV    1.264V
3.591ns   1.196V     645.5mV    1.265V
5.046ns   1.199V     1.13V      1.265V
20ns      1.2V       1.14V      1.265V
[Falling Waveform]
R_fixture= 50.000
V_fixture= 1.200
V_fixture_min= 1.140
V_fixture_max= 1.260
|time   V(typ)   V(min)   V(max)
0s        1.2V       1.14V      1.265V
1.037ns   1.2V       1.14V      1.323V
1.294ns   1.2V       1.14V      392.3mV
1.604ns   1.201V     1.14V      237mV
2.219ns   1.236V     1.14V      222.3mV
2.722ns   537.8mV    1.14V      219.8mV
3.314ns   413.8mV    1.14V      218.3mV
4.544ns   398mV      1.159V     217.9mV
6.204ns   395.2mV    695mV      217.9mV
20ns      394.6mV    678.9mV    217.9mV
[Falling Waveform]
R_fixture= 50.000
V_fixture= 0.0
V_fixture_min= 0.0
V_fixture_max= 0.0
|time   V(typ)   V(min)   V(max)
0s        561.3mV    340.2mV    932.2mV
945ps     561.4mV    340.3mV    927.7mV
1.028ns   561.4mV    340.3mV    753.2mV
1.175ns   561.4mV    340.3mV    112.9mV
1.347ns   561.4mV    340.3mV    15.19mV
1.942ns   553.7mV    340.3mV    2.73mV
2.571ns   13.51mV    340.3mV    769.1uV
3.855ns   1.089mV    339.1mV    61.15uV
5.171ns   255.6uV    5.066mV    24.05uV
20ns      -442.6nV   -793.9nV   -429.1nV
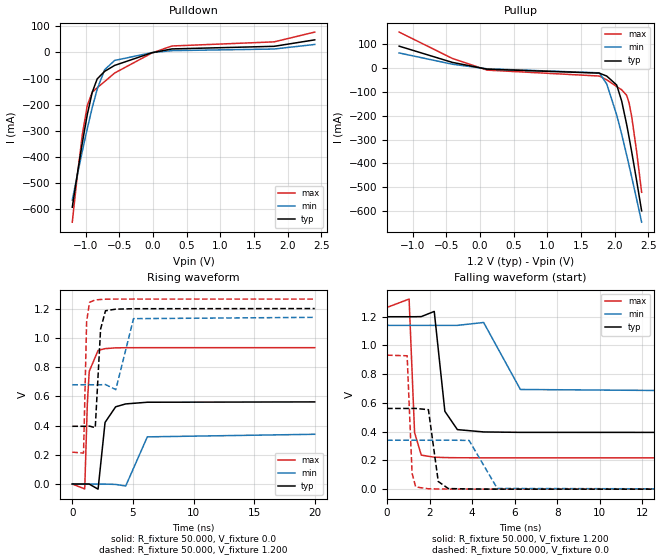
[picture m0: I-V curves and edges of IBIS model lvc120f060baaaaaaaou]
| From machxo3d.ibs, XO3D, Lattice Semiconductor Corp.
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|   Model lvc120f060baaaaaaaou
[Model] lvc120f060baaaaaaaou
Model_type Output
Polarity   Non-Inverting
Enable   Active-High
Vmeas =  0.600V
Cref =  0.0F
Rref =  1.000M
Vref =  0.0V
C_comp   4.200pF   3.800pF   7.500pF
[Temperature Range]   25.000   0.105k   -40.000
[Voltage Range]   1.200V   1.140V   1.260V
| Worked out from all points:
|   slope of the pulldown table from 0 to 0.18 V, typ, clamps not added: 18.4 ohm
|   slope of the pullup table from 0 to 0.18 V, typ, clamps not added: 28.4 ohm
|   rising waveform, R_fixture 50.000, V_fixture 0.0: 20-80 % time 469ps typ, 634ps min, 254ps max; typ from 0 V to 0.562 V
|   rising waveform, R_fixture 50.000, V_fixture 1.200: 20-80 % time 302ps typ, 481ps min, 141ps max; typ from 0.395 V to 1.2 V
|   falling waveform, R_fixture 50.000, V_fixture 1.200: 20-80 % time 346ps typ, 588ps min, 159ps max; typ from 1.2 V to 0.395 V
|   falling waveform, R_fixture 50.000, V_fixture 0.0: 20-80 % time 281ps typ, 496ps min, 120ps max; typ from 0.562 V to 0 V
[Pulldown]
|Voltage   I(typ)   I(min)   I(max)
-1.2V     -591.8mA   -564.5mA   -649mA
-1.126V   -466.6mA   -470.4mA   -473.7mA
-1.052V   -347.3mA   -379.1mA   -316.6mA
-978mV    -238.8mA   -292mA     -203.7mA
-904mV    -152.5mA   -211.3mA   -152.2mA
-830mV    -101.2mA   -140.6mA   -135.1mA
-719mV    -72.27mA   -65.9mA    -111.2mA
-571mV    -49.64mA   -30.72mA   -78.74mA
-16mV     -1.092mA   -579.7uA   -1.991mA
280mV     13.38mA    6.801mA    24.62mA
1.797V    23.34mA    13mA       40.36mA
2.4V      48.04mA    30.47mA    77.74mA
[Pullup]
|Voltage   I(typ)   I(min)   I(max)
-1.2V     92.74mA    64.16mA    151.9mA
-412mV    24.62mA    16.88mA    41.35mA
106mV     -4.071mA   -2.587mA   -8.015mA
1.771V    -20.72mA   -19.45mA   -32.9mA
1.882V    -33.02mA   -66.15mA   -48.77mA
2.03V     -70.75mA   -196.6mA   -77.4mA
2.104V    -138.2mA   -278mA     -90.83mA
2.178V    -236.9mA   -365.4mA   -114mA
2.215V    -292.6mA   -410.8mA   -147.4mA
2.252V    -350.9mA   -456.9mA   -202.3mA
2.326V    -473mA     -551.2mA   -350.5mA
2.4V      -599.8mA   -647.5mA   -521.7mA
[Ramp]
| variable   typ   min   max
dV/dt_r   0.337/0.469n   0.204/0.622n   0.559/0.253n
dV/dt_f   0.483/0.344n   0.277/0.596n   0.628/0.160n
R_load = 50.000
[Rising Waveform]
R_fixture= 50.000
V_fixture= 0.0
V_fixture_min= 0.0
V_fixture_max= 0.0
|time   V(typ)   V(min)   V(max)
0s        138.6uV    95.11uV    209.2uV
1.027ns   159.8uV    101.5uV    -32.99mV
1.242ns   221.6uV    101.5uV    549.7mV
1.399ns   10.23uV    101.5uV    770.7mV
2.128ns   -34.84mV   126.3uV    913.8mV
2.704ns   421.6mV    -147.6uV   926mV
3.576ns   528.2mV    -2.353mV   931.4mV
4.407ns   548.1mV    -13.06mV   932.3mV
6.19ns    559.5mV    322.8mV    932.6mV
20ns      561.8mV    340.5mV    932.6mV
[Rising Waveform]
R_fixture= 50.000
V_fixture= 1.200
V_fixture_min= 1.140
V_fixture_max= 1.260
|time   V(typ)   V(min)   V(max)
0s        395.1mV    679.1mV    218.3mV
929ps     395.1mV    679.1mV    211.8mV
1.184ns   394.8mV    679.1mV    1.111V
1.424ns   396.2mV    679.1mV    1.243V
1.896ns   385.6mV    678.8mV    1.259V
2.336ns   1.06V      679mV      1.262V
2.738ns   1.185V     680.6mV    1.264V
3.591ns   1.196V     645.8mV    1.265V
5.052ns   1.199V     1.131V     1.265V
20ns      1.2V       1.14V      1.265V
[Falling Waveform]
R_fixture= 50.000
V_fixture= 1.200
V_fixture_min= 1.140
V_fixture_max= 1.260
|time   V(typ)   V(min)   V(max)
0s        1.2V       1.14V      1.265V
1.037ns   1.2V       1.14V      1.323V
1.294ns   1.2V       1.14V      393.4mV
1.609ns   1.201V     1.14V      237.1mV
2.218ns   1.237V     1.14V      222.5mV
2.717ns   541.9mV    1.14V      220mV
3.305ns   414.5mV    1.14V      218.7mV
4.538ns   398.3mV    1.16V      218.3mV
6.265ns   395.4mV    693.8mV    218.2mV
20ns      395mV      679.1mV    218.2mV
[Falling Waveform]
R_fixture= 50.000
V_fixture= 0.0
V_fixture_min= 0.0
V_fixture_max= 0.0
|time   V(typ)   V(min)   V(max)
0s        561.8mV    340.5mV    932.6mV
945ps     561.9mV    340.6mV    928.2mV
1.176ns   561.9mV    340.6mV    111.4mV
1.346ns   561.9mV    340.6mV    15.53mV
1.945ns   553.1mV    340.5mV    2.877mV
2.407ns   53.36mV    340.5mV    1.371mV
2.878ns   4.433mV    341.2mV    622.5uV
3.855ns   1.289mV    339.3mV    263.3uV
5.18ns    324.5uV    5.032mV    229.4uV
20ns      138.2uV    94.26uV    208.8uV
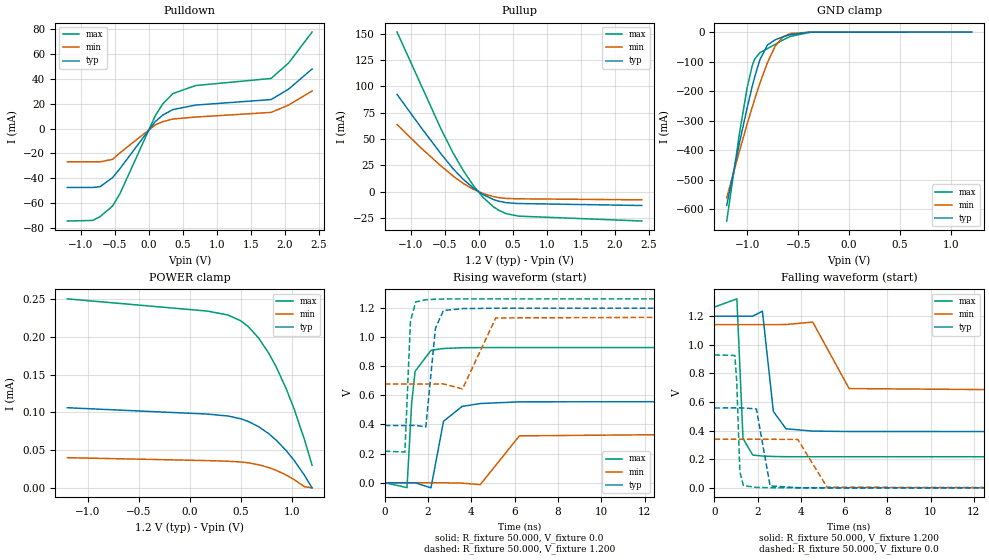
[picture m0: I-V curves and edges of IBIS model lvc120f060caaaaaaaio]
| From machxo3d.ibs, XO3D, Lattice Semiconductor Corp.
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|   Model lvc120f060caaaaaaaio
[Model] lvc120f060caaaaaaaio
Model_type I/O
Polarity   Non-Inverting
Enable   Active-Low
Vinl =  0.420V
Vinh =  0.780V
Vmeas =  0.600V
Cref =  0.0F
Rref =  1.000M
Vref =  0.0V
C_comp   4.200pF   3.800pF   7.500pF
[Temperature Range]   25.000   0.105k   -40.000
[Voltage Range]   1.200V   1.140V   1.260V
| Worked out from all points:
|   slope of the pulldown table from 0 to 0.18 V, typ, clamps not added: 18.4 ohm
|   slope of the pullup table from 0 to 0.18 V, typ, clamps not added: 28.4 ohm
|   GND clamp passes 1 mA (typ) near -0.44 V on its own axis
|   rising waveform, R_fixture 50.000, V_fixture 0.0: 20-80 % time 468ps typ, 625ps min, 257ps max; typ from 0 V to 0.557 V
|   rising waveform, R_fixture 50.000, V_fixture 1.200: 20-80 % time 303ps typ, 482ps min, 141ps max; typ from 0.393 V to 1.2 V
|   falling waveform, R_fixture 50.000, V_fixture 1.200: 20-80 % time 344ps typ, 589ps min, 159ps max; typ from 1.2 V to 0.393 V
|   falling waveform, R_fixture 50.000, V_fixture 0.0: 20-80 % time 277ps typ, 492ps min, 119ps max; typ from 0.557 V to 0 V
[Pulldown]
|Voltage   I(typ)   I(min)   I(max)
-1.2V     -47.32mA   -26.76mA   -74.29mA
-830mV    -47.32mA   -26.76mA   -73.83mA
-719mV    -46.75mA   -26.76mA   -70.83mA
-534mV    -39.41mA   -24.7mA    -62.22mA
-423mV    -32.02mA   -19.39mA   -52.05mA
95mV      5.729mA    2.992mA    10.49mA
206mV     10.86mA    5.583mA    19.95mA
354mV     15.29mA    7.674mA    28.14mA
687mV     18.86mA    9.24mA     34.55mA
1.797V    23.28mA    12.97mA    40.23mA
2.056V    31.76mA    18.91mA    52.74mA
2.4V      47.86mA    30.18mA    77.54mA
[Pullup]
|Voltage   I(typ)   I(min)   I(max)
-1.2V     92.55mA    63.89mA    151.7mA
-856mV    61.9mA     42.15mA    102.8mA
-560mV    36.57mA    24.92mA    60.59mA
-375mV    21.84mA    14.95mA    36.79mA
-227mV    11.91mA    7.992mA    20.32mA
-79mV     3.668mA    2.398mA    6.116mA
69mV      -2.76mA    -1.76mA    -5.559mA
217mV     -7.275mA   -4.565mA   -14.19mA
291mV     -8.829mA   -5.482mA   -17.35mA
402mV     -10.32mA   -6.287mA   -20.71mA
587mV     -11.14mA   -6.66mA    -23.11mA
2.4V      -13.01mA   -7.655mA   -27.74mA
[GND_clamp]
|Voltage   I(typ)   I(min)   I(max)
-1.2V     -586.8mA   -561.7mA   -640.4mA
-1.075V   -375.3mA   -403.2mA   -342.9mA
-1V       -256.8mA   -312.4mA   -188.9mA
-950mV    -184.3mA   -254.5mA   -114.1mA
-925mV    -151.1mA   -226.6mA   -91.32mA
-875mV    -94.01mA   -173.6mA   -70.06mA
-800mV    -43.56mA   -102.9mA   -56.11mA
-725mV    -26.45mA   -48.06mA   -41.65mA
-650mV    -16.55mA   -16.39mA   -27.24mA
-575mV    -8.728mA   -5.059mA   -14.79mA
-375mV    -266.5uA   -129.3uA   -404.6uA
1.2V      0A         0A         0A
[POWER_clamp]
|Voltage   I(typ)   I(min)   I(max)
-1.2V     106.1uA    39.97uA    250.3uA
175mV     97.7uA     36.09uA    234.1uA
375mV     95.13uA    35.25uA    228.9uA
500mV     91.53uA    34.24uA    221.3uA
575mV     87.92uA    33.12uA    213.4uA
675mV     81.09uA    30.65uA    198.5uA
775mV     71.72uA    26.88uA    178.3uA
850mV     62.93uA    23.1uA     159.7uA
950mV     48.73uA    16.7uA     130.1uA
1.025V    36.14uA    10.83uA    104uA
1.125V    16.67uA    1.54uA     64.01uA
1.2V      0A         0A         29.9uA
[Ramp]
| variable   typ   min   max
dV/dt_r   0.334/0.471n   0.203/0.625n   0.557/0.248n
dV/dt_f   0.483/0.343n   0.277/0.601n   0.627/0.159n
R_load = 50.000
[Rising Waveform]
R_fixture= 50.000
V_fixture= 0.0
V_fixture_min= 0.0
V_fixture_max= 0.0
|time   V(typ)   V(min)   V(max)
0s        2.225nV    32.56nV    936.2pV
1.027ns   -6.8uV     6.474uV    -33.26mV
1.242ns   24.62uV    6.474uV    546.6mV
1.399ns   -114.3uV   6.474uV    764.2mV
2.133ns   -35.02mV   31.33uV    908.8mV
2.713ns   421.9mV    -253.6uV   921.5mV
3.572ns   523.9mV    -2.587mV   926.6mV
4.407ns   543.8mV    -13.17mV   927.5mV
6.217ns   555.2mV    321.8mV    927.8mV
20ns      557.4mV    339mV      927.8mV
[Rising Waveform]
R_fixture= 50.000
V_fixture= 1.200
V_fixture_min= 1.140
V_fixture_max= 1.260
|time   V(typ)   V(min)   V(max)
0s        392.9mV    677.3mV    216.8mV
929ps     392.9mV    677.4mV    210.4mV
1.185ns   392.7mV    677.3mV    1.108V
1.427ns   394mV      677.3mV    1.241V
1.894ns   382.4mV    677.2mV    1.256V
2.339ns   1.06V      677.3mV    1.26V
2.707ns   1.182V     678.8mV    1.261V
3.591ns   1.195V     644mV      1.262V
5.123ns   1.198V     1.131V     1.262V
20ns      1.198V     1.139V     1.262V
[Falling Waveform]
R_fixture= 50.000
V_fixture= 1.200
V_fixture_min= 1.140
V_fixture_max= 1.260
|time   V(typ)   V(min)   V(max)
0s        1.198V     1.139V     1.262V
1.036ns   1.198V     1.139V     1.319V
1.32ns    1.198V     1.139V     344.1mV
1.769ns   1.198V     1.139V     228.7mV
2.218ns   1.233V     1.139V     221.9mV
2.724ns   533.5mV    1.139V     218.8mV
3.311ns   412.1mV    1.14V      217.3mV
4.547ns   396.2mV    1.157V     216.9mV
6.231ns   393.3mV    693mV      216.9mV
20ns      392.9mV    677.3mV    216.8mV
[Falling Waveform]
R_fixture= 50.000
V_fixture= 0.0
V_fixture_min= 0.0
V_fixture_max= 0.0
|time   V(typ)   V(min)   V(max)
0s        557.4mV    339mV      927.8mV
943ps     557.5mV    339.1mV    924.1mV
1.028ns   557.5mV    339.1mV    746.6mV
1.174ns   557.5mV    339.1mV    111.5mV
1.338ns   557.5mV    339.1mV    15.78mV
1.939ns   550.9mV    339mV      3.129mV
2.575ns   13.22mV    339.1mV    768.4uV
3.855ns   1.165mV    337.8mV    56.11uV
5.211ns   192.9uV    4.605mV    21.05uV
20ns      -538.9nV   -1.128uV   -614.9nV
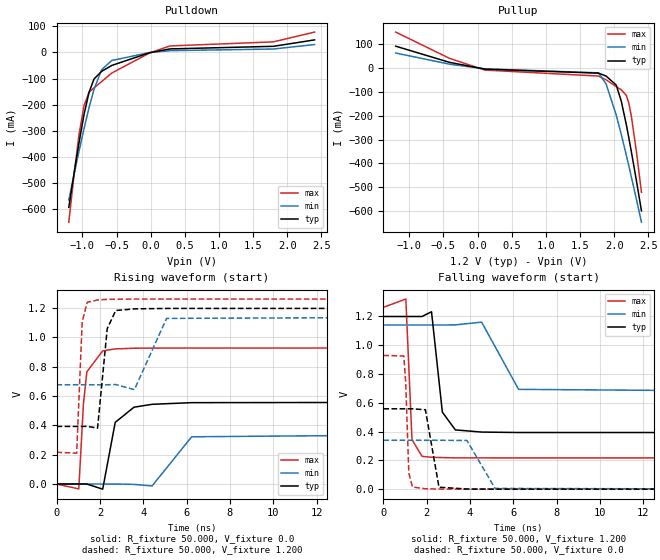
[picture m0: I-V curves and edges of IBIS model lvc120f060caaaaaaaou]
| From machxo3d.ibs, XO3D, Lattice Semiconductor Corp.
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|   Model lvc120f060caaaaaaaou
[Model] lvc120f060caaaaaaaou
Model_type Output
Polarity   Non-Inverting
Enable   Active-High
Vmeas =  0.600V
Cref =  0.0F
Rref =  1.000M
Vref =  0.0V
C_comp   4.200pF   3.800pF   7.500pF
[Temperature Range]   25.000   0.105k   -40.000
[Voltage Range]   1.200V   1.140V   1.260V
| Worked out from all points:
|   slope of the pulldown table from 0 to 0.18 V, typ, clamps not added: 18.3 ohm
|   slope of the pullup table from 0 to 0.18 V, typ, clamps not added: 28.4 ohm
|   rising waveform, R_fixture 50.000, V_fixture 0.0: 20-80 % time 467ps typ, 633ps min, 255ps max; typ from 0 V to 0.557 V
|   rising waveform, R_fixture 50.000, V_fixture 1.200: 20-80 % time 303ps typ, 482ps min, 141ps max; typ from 0.393 V to 1.2 V
|   falling waveform, R_fixture 50.000, V_fixture 1.200: 20-80 % time 343ps typ, 589ps min, 159ps max; typ from 1.2 V to 0.393 V
|   falling waveform, R_fixture 50.000, V_fixture 0.0: 20-80 % time 279ps typ, 495ps min, 119ps max; typ from 0.557 V to 0 V
[Pulldown]
|Voltage   I(typ)   I(min)   I(max)
-1.2V     -591.8mA   -564.5mA   -649mA
-1.126V   -466.6mA   -470.4mA   -473.8mA
-1.052V   -347.3mA   -379.1mA   -316.6mA
-978mV    -238.8mA   -292mA     -203.8mA
-904mV    -152.6mA   -211.3mA   -152.3mA
-830mV    -101.2mA   -140.6mA   -135.2mA
-719mV    -72.31mA   -65.93mA   -111.3mA
-571mV    -49.7mA    -30.76mA   -78.81mA
-16mV     -1.084mA   -576.1uA   -1.969mA
280mV     13.45mA    6.829mA    24.77mA
1.797V    23.39mA    13mA       40.48mA
2.4V      47.96mA    30.22mA    77.79mA
[Pullup]
|Voltage   I(typ)   I(min)   I(max)
-1.2V     92.65mA    63.93mA    151.9mA
-412mV    24.69mA    16.91mA    41.52mA
106mV     -3.969mA   -2.548mA   -7.771mA
1.771V    -20.76mA   -19.48mA   -32.97mA
1.882V    -33.04mA   -66.17mA   -48.81mA
2.03V     -70.79mA   -196.6mA   -77.42mA
2.104V    -138.2mA   -278mA     -90.85mA
2.178V    -237mA     -365.4mA   -114mA
2.215V    -292.6mA   -410.8mA   -147.4mA
2.252V    -351mA     -456.9mA   -202.3mA
2.326V    -473mA     -551.2mA   -350.6mA
2.4V      -599.8mA   -647.5mA   -521.8mA
[Ramp]
| variable   typ   min   max
dV/dt_r   0.334/0.465n   0.203/0.621n   0.557/0.254n
dV/dt_f   0.483/0.342n   0.277/0.600n   0.627/0.159n
R_load = 50.000
[Rising Waveform]
R_fixture= 50.000
V_fixture= 0.0
V_fixture_min= 0.0
V_fixture_max= 0.0
|time   V(typ)   V(min)   V(max)
0s        2.212nV    32.68nV    920.7pV
1.027ns   20.63uV    5.752uV    -33.3mV
1.242ns   85.24uV    5.752uV    547.4mV
1.399ns   -114.9uV   5.752uV    765.6mV
2.13ns    -35.07mV   30.61uV    908.7mV
2.708ns   420.9mV    -249.8uV   922mV
3.576ns   524.3mV    -2.442mV   926.6mV
4.407ns   543.9mV    -13.21mV   927.5mV
6.236ns   555.2mV    322.3mV    927.8mV
20ns      557.4mV    339mV      927.8mV
[Rising Waveform]
R_fixture= 50.000
V_fixture= 1.200
V_fixture_min= 1.140
V_fixture_max= 1.260
|time   V(typ)   V(min)   V(max)
0s        392.9mV    677.3mV    216.8mV
929ps     392.9mV    677.4mV    210.4mV
1.185ns   392.7mV    677.4mV    1.109V
1.418ns   394mV      677.4mV    1.24V
1.892ns   381.2mV    677mV      1.256V
2.339ns   1.06V      677.3mV    1.26V
2.731ns   1.184V     678.9mV    1.261V
3.591ns   1.195V     644mV      1.262V
5.076ns   1.198V     1.13V      1.262V
20ns      1.198V     1.139V     1.262V
[Falling Waveform]
R_fixture= 50.000
V_fixture= 1.200
V_fixture_min= 1.140
V_fixture_max= 1.260
|time   V(typ)   V(min)   V(max)
0s        1.198V     1.139V     1.262V
1.036ns   1.198V     1.139V     1.319V
1.32ns    1.198V     1.139V     343.7mV
1.783ns   1.198V     1.139V     227.9mV
2.222ns   1.231V     1.139V     221.4mV
2.722ns   534.4mV    1.139V     219.1mV
3.323ns   411.2mV    1.14V      217.2mV
4.536ns   396.2mV    1.159V     216.9mV
6.242ns   393.1mV    692.5mV    216.8mV
20ns      392.9mV    677.3mV    216.8mV
[Falling Waveform]
R_fixture= 50.000
V_fixture= 0.0
V_fixture_min= 0.0
V_fixture_max= 0.0
|time   V(typ)   V(min)   V(max)
0s        557.4mV    339mV      927.8mV
943ps     557.5mV    339.1mV    924.1mV
1.028ns   557.5mV    339.1mV    746.6mV
1.174ns   557.5mV    339.1mV    111.3mV
1.343ns   557.5mV    339.1mV    14.92mV
1.939ns   550.9mV    339mV      2.77mV
2.567ns   13.45mV    339.1mV    808.3uV
3.855ns   1.087mV    337.8mV    72.25uV
5.156ns   258.4uV    5.255mV    30.65uV
20ns      -484.5nV   -689.4nV   -490.2nV
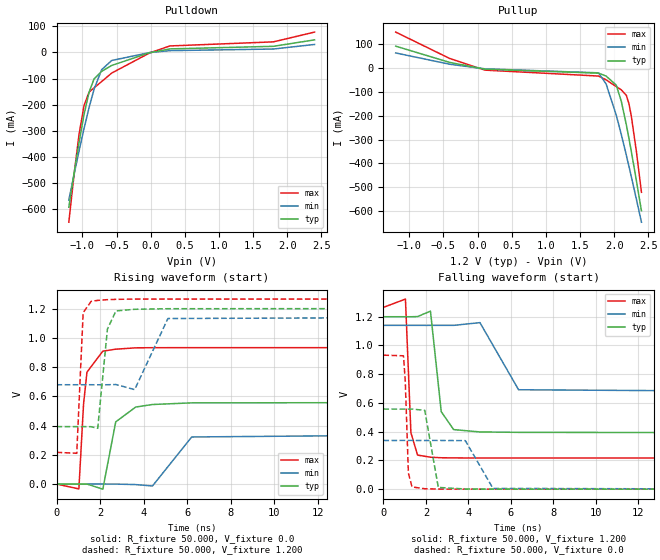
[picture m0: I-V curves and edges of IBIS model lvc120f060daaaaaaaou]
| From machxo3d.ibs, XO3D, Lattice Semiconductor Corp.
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|   Model lvc120f060daaaaaaaou
[Model] lvc120f060daaaaaaaou
Model_type Output
Polarity   Non-Inverting
Enable   Active-High
Vmeas =  0.600V
Cref =  0.0F
Rref =  1.000M
Vref =  0.0V
C_comp   4.200pF   3.800pF   7.500pF
[Temperature Range]   25.000   0.105k   -40.000
[Voltage Range]   1.200V   1.140V   1.260V
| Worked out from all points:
|   slope of the pulldown table from 0 to 0.18 V, typ, clamps not added: 18.3 ohm
|   slope of the pullup table from 0 to 0.18 V, typ, clamps not added: 28.4 ohm
|   rising waveform, R_fixture 50.000, V_fixture 0.0: 20-80 % time 469ps typ, 622ps min, 250ps max; typ from 0 V to 0.557 V
|   rising waveform, R_fixture 50.000, V_fixture 1.200: 20-80 % time 304ps typ, 478ps min, 142ps max; typ from 0.393 V to 1.2 V
|   falling waveform, R_fixture 50.000, V_fixture 1.200: 20-80 % time 349ps typ, 588ps min, 160ps max; typ from 1.2 V to 0.393 V
|   falling waveform, R_fixture 50.000, V_fixture 0.0: 20-80 % time 280ps typ, 494ps min, 120ps max; typ from 0.557 V to 0 V
[Pulldown]
|Voltage   I(typ)   I(min)   I(max)
-1.2V     -591.8mA   -564.5mA   -649mA
-1.126V   -466.6mA   -470.4mA   -473.8mA
-1.052V   -347.3mA   -379.1mA   -316.6mA
-978mV    -238.8mA   -292mA     -203.8mA
-904mV    -152.6mA   -211.3mA   -152.3mA
-830mV    -101.2mA   -140.6mA   -135.2mA
-719mV    -72.31mA   -65.93mA   -111.3mA
-571mV    -49.7mA    -30.76mA   -78.81mA
-16mV     -1.084mA   -576.1uA   -1.969mA
280mV     13.45mA    6.829mA    24.77mA
1.797V    23.34mA    13mA       40.36mA
2.4V      48.04mA    30.47mA    77.74mA
[Pullup]
|Voltage   I(typ)   I(min)   I(max)
-1.2V     92.74mA    64.16mA    151.9mA
-412mV    24.62mA    16.88mA    41.35mA
106mV     -4.071mA   -2.587mA   -8.015mA
1.771V    -20.76mA   -19.48mA   -32.97mA
1.882V    -33.04mA   -66.17mA   -48.81mA
2.03V     -70.79mA   -196.6mA   -77.42mA
2.104V    -138.2mA   -278mA     -90.85mA
2.178V    -237mA     -365.4mA   -114mA
2.215V    -292.6mA   -410.8mA   -147.4mA
2.252V    -351mA     -456.9mA   -202.3mA
2.326V    -473mA     -551.2mA   -350.6mA
2.4V      -599.8mA   -647.5mA   -521.8mA
[Ramp]
| variable   typ   min   max
dV/dt_r   0.334/0.465n   0.203/0.621n   0.560/0.258n
dV/dt_f   0.484/0.347n   0.277/0.596n   0.629/0.161n
R_load = 50.000
[Rising Waveform]
R_fixture= 50.000
V_fixture= 0.0
V_fixture_min= 0.0
V_fixture_max= 0.0
|time   V(typ)   V(min)   V(max)
0s        2.212nV    32.68nV    920.7pV
1.027ns   20.69uV    5.738uV    -33.3mV
1.242ns   85.24uV    5.738uV    547.4mV
1.399ns   -114.9uV   5.738uV    765.6mV
2.127ns   -35.03mV   30.61uV    908.7mV
2.72ns    425.1mV    -249.8uV   922.2mV
3.637ns   526.5mV    -3.689mV   931.5mV
4.407ns   543.9mV    -13.21mV   932.4mV
6.211ns   555.2mV    321.9mV    932.6mV
20ns      557.4mV    339mV      932.6mV
[Rising Waveform]
R_fixture= 50.000
V_fixture= 1.200
V_fixture_min= 1.140
V_fixture_max= 1.260
|time   V(typ)   V(min)   V(max)
0s        392.9mV    679.1mV    216.8mV
929ps     392.9mV    679.1mV    210.4mV
1.224ns   392.8mV    679.1mV    1.172V
1.588ns   392.1mV    679.1mV    1.249V
1.892ns   381.2mV    678.8mV    1.256V
2.339ns   1.06V      679mV      1.261V
2.731ns   1.184V     680.6mV    1.263V
3.591ns   1.195V     645.8mV    1.265V
5.118ns   1.199V     1.132V     1.265V
20ns      1.2V       1.14V      1.265V
[Falling Waveform]
R_fixture= 50.000
V_fixture= 1.200
V_fixture_min= 1.140
V_fixture_max= 1.260
|time   V(typ)   V(min)   V(max)
0s        1.2V       1.14V      1.265V
1.037ns   1.2V       1.14V      1.323V
1.294ns   1.2V       1.14V      393.4mV
1.607ns   1.201V     1.14V      237.2mV
2.214ns   1.239V     1.14V      222.5mV
2.721ns   539.3mV    1.14V      218.6mV
3.305ns   414.5mV    1.14V      217.5mV
4.542ns   398.3mV    1.159V     216.9mV
6.36ns    395.4mV    691.9mV    216.9mV
20ns      392.9mV    679.1mV    216.8mV
[Falling Waveform]
R_fixture= 50.000
V_fixture= 0.0
V_fixture_min= 0.0
V_fixture_max= 0.0
|time   V(typ)   V(min)   V(max)
0s        557.4mV    339mV      932.6mV
945ps     557.5mV    339.1mV    928.2mV
1.028ns   557.5mV    339.1mV    753.9mV
1.176ns   557.5mV    339.1mV    111.4mV
1.346ns   557.5mV    339.1mV    15.53mV
1.945ns   548.7mV    339mV      2.881mV
2.583ns   12.19mV    339.1mV    774.6uV
3.855ns   1.087mV    337.8mV    65.29uV
5.156ns   257.4uV    5.255mV    26.23uV
20ns      -484.5nV   -689.4nV   -562.1nV
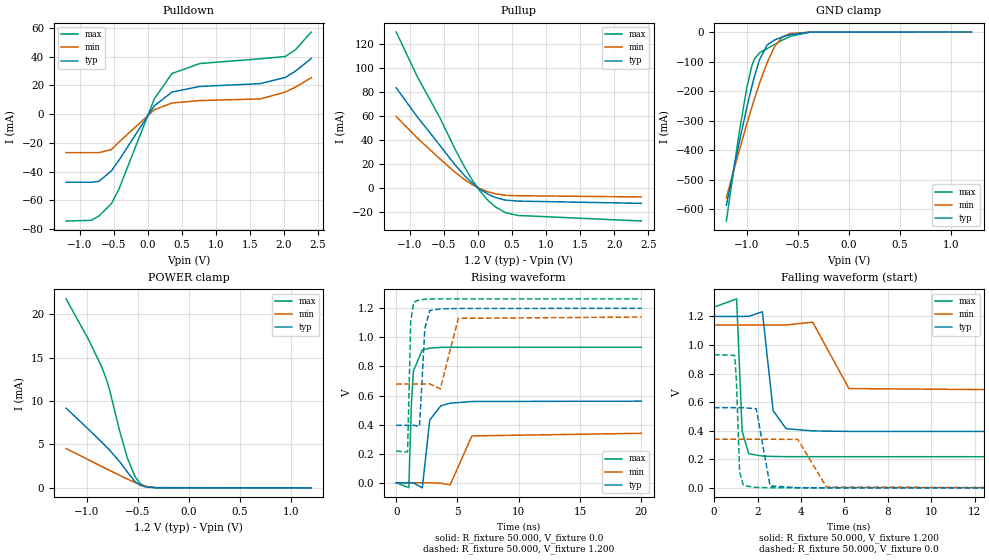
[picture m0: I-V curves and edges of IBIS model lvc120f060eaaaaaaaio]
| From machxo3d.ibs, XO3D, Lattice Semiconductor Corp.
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|   Model lvc120f060eaaaaaaaio
[Model] lvc120f060eaaaaaaaio
Model_type I/O
Polarity   Non-Inverting
Enable   Active-Low
Vinl =  0.420V
Vinh =  0.780V
Vmeas =  0.600V
Cref =  0.0F
Rref =  1.000M
Vref =  0.0V
C_comp   4.200pF   3.800pF   7.500pF
[Temperature Range]   25.000   0.105k   -40.000
[Voltage Range]   1.200V   1.140V   1.260V
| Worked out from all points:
|   slope of the pulldown table from 0 to 0.18 V, typ, clamps not added: 18.4 ohm
|   slope of the pullup table from 0 to 0.18 V, typ, clamps not added: 28.4 ohm
|   GND clamp passes 1 mA (typ) near -0.44 V on its own axis
|   POWER clamp passes 1 mA (typ) near -0.55 V on its own axis
|   rising waveform, R_fixture 50.000, V_fixture 0.0: 20-80 % time 477ps typ, 635ps min, 247ps max; typ from 0 V to 0.561 V
|   rising waveform, R_fixture 50.000, V_fixture 1.200: 20-80 % time 303ps typ, 479ps min, 141ps max; typ from 0.395 V to 1.2 V
|   falling waveform, R_fixture 50.000, V_fixture 1.200: 20-80 % time 345ps typ, 598ps min, 159ps max; typ from 1.2 V to 0.395 V
|   falling waveform, R_fixture 50.000, V_fixture 0.0: 20-80 % time 279ps typ, 497ps min, 120ps max; typ from 0.561 V to 0 V
[Pulldown]
|Voltage   I(typ)   I(min)   I(max)
-1.2V     -47.32mA   -26.76mA   -74.28mA
-830mV    -47.32mA   -26.76mA   -73.83mA
-719mV    -46.75mA   -26.76mA   -70.83mA
-534mV    -39.41mA   -24.7mA    -62.22mA
-423mV    -32.02mA   -19.39mA   -52.05mA
95mV      5.729mA    2.992mA    10.49mA
354mV     15.29mA    7.674mA    28.14mA
761mV     19.19mA    9.392mA    35.13mA
1.649V    21.15mA    10.52mA    38.38mA
2.019V    25.44mA    15.26mA    40mA
2.167V    29.79mA    18.68mA    44.62mA
2.4V      38.62mA    25.27mA    57mA
[Pullup]
|Voltage   I(typ)   I(min)   I(max)
-1.2V     83.3mA     59.33mA    129.8mA
-893mV    59.32mA    41.69mA    92.95mA
-560mV    35.41mA    24.12mA    58.49mA
-338mV    19.19mA    13.06mA    32.47mA
-190mV    9.687mA    6.463mA    16.55mA
-79mV     3.668mA    2.398mA    6.116mA
32mV      -1.332mA   -852.4uA   -2.917mA
143mV     -5.255mA   -3.327mA   -10.26mA
254mV     -8.11mA    -5.063mA   -15.86mA
402mV     -10.32mA   -6.287mA   -20.71mA
587mV     -11.14mA   -6.66mA    -23.11mA
2.4V      -13.01mA   -7.655mA   -27.74mA
[GND_clamp]
|Voltage   I(typ)   I(min)   I(max)
-1.2V     -586.8mA   -561.6mA   -640.3mA
-1.075V   -375.3mA   -403.2mA   -342.9mA
-1V       -256.8mA   -312.3mA   -188.8mA
-950mV    -184.3mA   -254.5mA   -114.1mA
-925mV    -151.1mA   -226.6mA   -91.26mA
-875mV    -93.95mA   -173.6mA   -69.99mA
-800mV    -43.5mA    -102.9mA   -56.04mA
-725mV    -26.4mA    -48.03mA   -41.57mA
-650mV    -16.5mA    -16.35mA   -27.16mA
-575mV    -8.667mA   -5.012mA   -14.69mA
-375mV    -183.5uA   -82.46uA   -270.8uA
1.2V      0A         0A         0A
[POWER_clamp]
|Voltage   I(typ)   I(min)   I(max)
-1.2V     9.182mA    4.531mA    21.77mA
-975mV    6.68mA     3.195mA    16.97mA
-850mV    5.256mA    2.452mA    13.9mA
-800mV    4.662mA    2.159mA    12.31mA
-775mV    4.355mA    2.014mA    11.32mA
-675mV    3.015mA    1.438mA    6.52mA
-600mV    1.813mA    1.015mA    3.43mA
-525mV    717.6uA    612.9uA    1.296mA
-475mV    302.2uA    372.2uA    507.9uA
-425mV    111uA      180.2uA    159.4uA
-325mV    13.15uA    20.51uA    12.23uA
1.2V      0A         0A         3.808nA
[Ramp]
| variable   typ   min   max
dV/dt_r   0.337/0.473n   0.204/0.623n   0.559/0.255n
dV/dt_f   0.483/0.344n   0.277/0.596n   0.628/0.160n
R_load = 50.000
[Rising Waveform]
R_fixture= 50.000
V_fixture= 0.0
V_fixture_min= 0.0
V_fixture_max= 0.0
|time   V(typ)   V(min)   V(max)
0s        2.304nV    32.88nV    1.018nV
1.027ns   -6.797uV   6.516uV    -33.38mV
1.242ns   24.92uV    6.516uV    547.9mV
1.399ns   -110.7uV   6.516uV    768.2mV
2.128ns   -35.1mV    31.38uV    913.2mV
2.737ns   431.6mV    -253.7uV   926.4mV
3.641ns   529.8mV    -3.69mV    931.2mV
4.401ns   547.3mV    -14.1mV    931.9mV
6.177ns   558.9mV    322.1mV    932.2mV
20ns      561.3mV    340.2mV    932.3mV
[Rising Waveform]
R_fixture= 50.000
V_fixture= 1.200
V_fixture_min= 1.140
V_fixture_max= 1.260
|time   V(typ)   V(min)   V(max)
0s        394.7mV    678.9mV    217.9mV
929ps     394.7mV    679mV      211.5mV
1.184ns   394.5mV    678.9mV    1.11V
1.425ns   395.8mV    678.9mV    1.243V
1.898ns   386.6mV    678.8mV    1.258V
2.339ns   1.063V     678.8mV    1.262V
2.734ns   1.185V     680.4mV    1.264V
3.591ns   1.196V     645.5mV    1.265V
5.067ns   1.199V     1.131V     1.265V
20ns      1.2V       1.14V      1.265V
[Falling Waveform]
R_fixture= 50.000
V_fixture= 1.200
V_fixture_min= 1.140
V_fixture_max= 1.260
|time   V(typ)   V(min)   V(max)
0s        1.2V       1.14V      1.265V
1.037ns   1.2V       1.14V      1.323V
1.293ns   1.2V       1.14V      394.6mV
1.594ns   1.201V     1.14V      238.2mV
2.223ns   1.233V     1.14V      222.6mV
2.718ns   540.7mV    1.14V      219.7mV
3.311ns   414.3mV    1.14V      218.3mV
4.537ns   398.7mV    1.16V      218mV
6.204ns   395.2mV    695.2mV    217.9mV
20ns      394.6mV    678.9mV    217.9mV
[Falling Waveform]
R_fixture= 50.000
V_fixture= 0.0
V_fixture_min= 0.0
V_fixture_max= 0.0
|time   V(typ)   V(min)   V(max)
0s        561.3mV    340.2mV    932.2mV
945ps     561.4mV    340.3mV    927.7mV
1.028ns   561.4mV    340.3mV    753.2mV
1.175ns   561.4mV    340.3mV    113.1mV
1.348ns   561.4mV    340.3mV    15.58mV
1.942ns   553.7mV    340.3mV    2.986mV
2.577ns   13.47mV    340.3mV    742.2uV
3.855ns   1.048mV    339.1mV    56.26uV
5.174ns   240.6uV    5.237mV    21.35uV
20ns      -508.3nV   -940.8nV   -220.5nV
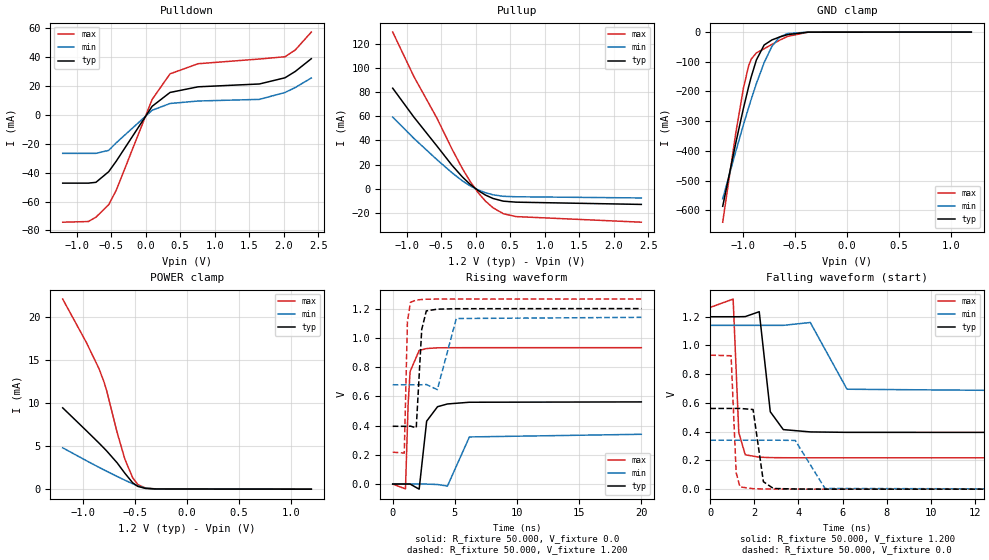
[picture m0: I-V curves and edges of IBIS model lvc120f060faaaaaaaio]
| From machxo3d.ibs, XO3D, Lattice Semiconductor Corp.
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|   Model lvc120f060faaaaaaaio
[Model] lvc120f060faaaaaaaio
Model_type I/O
Polarity   Non-Inverting
Enable   Active-Low
Vinl =  0.420V
Vinh =  0.780V
Vmeas =  0.600V
Cref =  0.0F
Rref =  1.000M
Vref =  0.0V
C_comp   4.200pF   3.800pF   7.500pF
[Temperature Range]   25.000   0.105k   -40.000
[Voltage Range]   1.200V   1.140V   1.260V
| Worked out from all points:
|   slope of the pulldown table from 0 to 0.18 V, typ, clamps not added: 18.4 ohm
|   slope of the pullup table from 0 to 0.18 V, typ, clamps not added: 28.4 ohm
|   GND clamp passes 1 mA (typ) near -0.44 V on its own axis
|   POWER clamp passes 1 mA (typ) near -0.55 V on its own axis
|   rising waveform, R_fixture 50.000, V_fixture 0.0: 20-80 % time 467ps typ, 641ps min, 256ps max; typ from 0 V to 0.562 V
|   rising waveform, R_fixture 50.000, V_fixture 1.200: 20-80 % time 303ps typ, 477ps min, 141ps max; typ from 0.395 V to 1.2 V
|   falling waveform, R_fixture 50.000, V_fixture 1.200: 20-80 % time 346ps typ, 589ps min, 160ps max; typ from 1.2 V to 0.395 V
|   falling waveform, R_fixture 50.000, V_fixture 0.0: 20-80 % time 282ps typ, 498ps min, 120ps max; typ from 0.562 V to 0 V
[Pulldown]
|Voltage   I(typ)   I(min)   I(max)
-1.2V     -47.32mA   -26.76mA   -74.28mA
-830mV    -47.32mA   -26.76mA   -73.83mA
-719mV    -46.75mA   -26.76mA   -70.83mA
-534mV    -39.41mA   -24.7mA    -62.22mA
-423mV    -32.02mA   -19.39mA   -52.05mA
95mV      5.729mA    2.992mA    10.49mA
354mV     15.29mA    7.674mA    28.14mA
761mV     19.19mA    9.392mA    35.13mA
1.649V    21.15mA    10.51mA    38.38mA
2.019V    25.43mA    15.27mA    39.95mA
2.167V    29.78mA    18.68mA    44.59mA
2.4V      38.6mA     25.28mA    56.97mA
[Pullup]
|Voltage   I(typ)   I(min)   I(max)
-1.2V     83.3mA     59.35mA    129.8mA
-893mV    59.32mA    41.69mA    92.93mA
-560mV    35.41mA    24.12mA    58.49mA
-338mV    19.19mA    13.06mA    32.47mA
-190mV    9.687mA    6.463mA    16.55mA
-79mV     3.668mA    2.398mA    6.116mA
32mV      -1.332mA   -852.4uA   -2.917mA
143mV     -5.255mA   -3.327mA   -10.26mA
254mV     -8.11mA    -5.063mA   -15.86mA
402mV     -10.32mA   -6.287mA   -20.71mA
587mV     -11.14mA   -6.66mA    -23.11mA
2.4V      -13.01mA   -7.655mA   -27.74mA
[GND_clamp]
|Voltage   I(typ)   I(min)   I(max)
-1.2V     -586.8mA   -561.6mA   -640.3mA
-1.075V   -375.3mA   -403.2mA   -342.9mA
-1V       -256.8mA   -312.3mA   -188.8mA
-950mV    -184.3mA   -254.5mA   -114mA
-925mV    -151.1mA   -226.6mA   -91.27mA
-875mV    -93.95mA   -173.6mA   -70mA
-800mV    -43.51mA   -102.9mA   -56.05mA
-725mV    -26.4mA    -48.03mA   -41.58mA
-650mV    -16.51mA   -16.35mA   -27.17mA
-575mV    -8.674mA   -5.016mA   -14.71mA
-375mV    -194.8uA   -87.66uA   -296.2uA
1.2V      -42.59nA   0A         -5.33uA
[POWER_clamp]
|Voltage   I(typ)   I(min)   I(max)
-1.2V     9.441mA    4.803mA    22.07mA
-975mV    6.83mA     3.329mA    17.11mA
-850mV    5.356mA    2.536mA    14mA
-800mV    4.744mA    2.228mA    12.4mA
-775mV    4.43mA     2.076mA    11.41mA
-675mV    3.065mA    1.478mA    6.596mA
-600mV    1.851mA    1.044mA    3.486mA
-525mV    744.7uA    632.6uA    1.337mA
-475mV    325.6uA    388.1uA    543.5uA
-400mV    86.39uA    124.7uA    120.1uA
-300mV    23.03uA    20.03uA    34.62uA
1.2V      0A         0A         0A
[Ramp]
| variable   typ   min   max
dV/dt_r   0.337/0.476n   0.204/0.623n   0.559/0.255n
dV/dt_f   0.483/0.345n   0.277/0.596n   0.628/0.160n
R_load = 50.000
[Rising Waveform]
R_fixture= 50.000
V_fixture= 0.0
V_fixture_min= 0.0
V_fixture_max= 0.0
|time   V(typ)   V(min)   V(max)
0s        138.6uV    95.1uV     209.2uV
1.027ns   160.9uV    102.6uV    -32.93mV
1.242ns   199uV      102.6uV    548.8mV
1.399ns   92.49uV    102.6uV    769.1mV
2.128ns   -34.79mV   127.4uV    913.5mV
2.731ns   430.2mV    -157.5uV   926.7mV
3.608ns   529.1mV    -2.927mV   931.6mV
4.403ns   547.8mV    -13.59mV   932.3mV
6.17ns    559.5mV    322.3mV    932.6mV
20ns      561.8mV    340.5mV    932.6mV
[Rising Waveform]
R_fixture= 50.000
V_fixture= 1.200
V_fixture_min= 1.140
V_fixture_max= 1.260
|time   V(typ)   V(min)   V(max)
0s        395.1mV    679.1mV    218.3mV
929ps     395mV      679.1mV    211.8mV
1.184ns   394.8mV    679.1mV    1.11V
1.424ns   396.2mV    679.1mV    1.243V
1.894ns   384.4mV    679mV      1.258V
2.334ns   1.057V     679mV      1.262V
2.704ns   1.184V     680.7mV    1.264V
3.591ns   1.196V     645.8mV    1.265V
5.116ns   1.199V     1.132V     1.265V
20ns      1.2V       1.14V      1.265V
[Falling Waveform]
R_fixture= 50.000
V_fixture= 1.200
V_fixture_min= 1.140
V_fixture_max= 1.260
|time   V(typ)   V(min)   V(max)
0s        1.2V       1.14V      1.265V
1.037ns   1.2V       1.14V      1.323V
1.294ns   1.2V       1.14V      393.7mV
1.587ns   1.201V     1.14V      239.1mV
2.221ns   1.235V     1.14V      222.7mV
2.722ns   539mV      1.14V      219.8mV
3.313ns   414.6mV    1.14V      218.8mV
4.537ns   398.5mV    1.16V      218.3mV
6.204ns   395.5mV    695.5mV    218.3mV
20ns      394.9mV    679.1mV    218.2mV
[Falling Waveform]
R_fixture= 50.000
V_fixture= 0.0
V_fixture_min= 0.0
V_fixture_max= 0.0
|time   V(typ)   V(min)   V(max)
0s        561.8mV    340.5mV    932.6mV
944ps     561.9mV    340.6mV    928.6mV
1.175ns   561.9mV    340.6mV    113.8mV
1.347ns   561.9mV    340.6mV    15.92mV
1.942ns   554.3mV    340.5mV    3.334mV
2.41ns    52.05mV    340.5mV    1.403mV
2.864ns   4.841mV    341.2mV    640.6uV
3.855ns   1.322mV    339.3mV    268.6uV
5.206ns   338.3uV    4.855mV    232.2uV
20ns      138.1uV    93.98uV    208.9uV
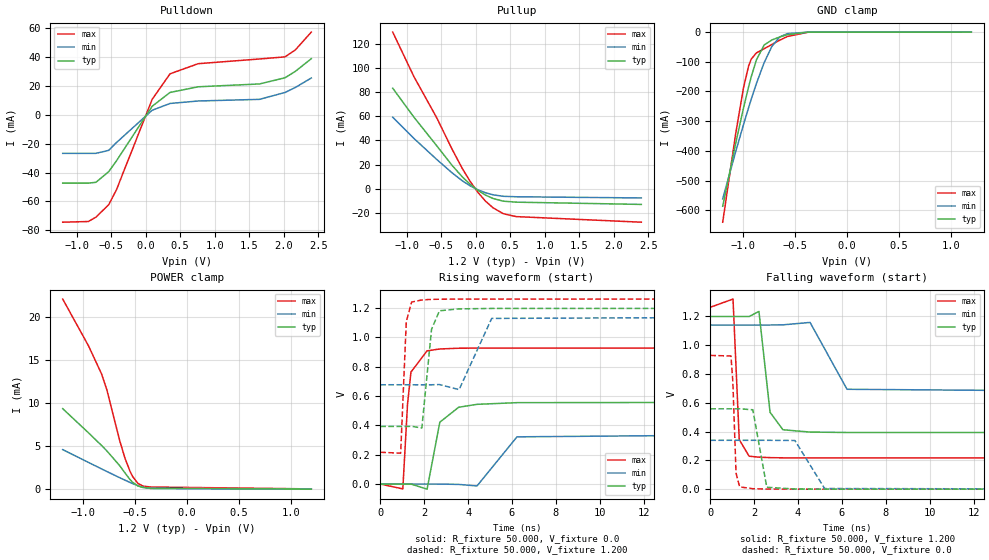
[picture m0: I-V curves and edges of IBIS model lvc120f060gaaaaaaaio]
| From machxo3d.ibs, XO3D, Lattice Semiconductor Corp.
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|   Model lvc120f060gaaaaaaaio
[Model] lvc120f060gaaaaaaaio
Model_type I/O
Polarity   Non-Inverting
Enable   Active-Low
Vinl =  0.420V
Vinh =  0.780V
Vmeas =  0.600V
Cref =  0.0F
Rref =  1.000M
Vref =  0.0V
C_comp   4.200pF   3.800pF   7.500pF
[Temperature Range]   25.000   0.105k   -40.000
[Voltage Range]   1.200V   1.140V   1.260V
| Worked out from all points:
|   slope of the pulldown table from 0 to 0.18 V, typ, clamps not added: 18.4 ohm
|   slope of the pullup table from 0 to 0.18 V, typ, clamps not added: 28.4 ohm
|   GND clamp passes 1 mA (typ) near -0.44 V on its own axis
|   POWER clamp passes 1 mA (typ) near -0.54 V on its own axis
|   rising waveform, R_fixture 50.000, V_fixture 0.0: 20-80 % time 468ps typ, 627ps min, 257ps max; typ from 0 V to 0.557 V
|   rising waveform, R_fixture 50.000, V_fixture 1.200: 20-80 % time 303ps typ, 481ps min, 141ps max; typ from 0.393 V to 1.2 V
|   falling waveform, R_fixture 50.000, V_fixture 1.200: 20-80 % time 344ps typ, 589ps min, 159ps max; typ from 1.2 V to 0.393 V
|   falling waveform, R_fixture 50.000, V_fixture 0.0: 20-80 % time 277ps typ, 492ps min, 119ps max; typ from 0.557 V to 0 V
[Pulldown]
|Voltage   I(typ)   I(min)   I(max)
-1.2V     -47.32mA   -26.76mA   -74.29mA
-830mV    -47.32mA   -26.76mA   -73.83mA
-719mV    -46.75mA   -26.76mA   -70.83mA
-534mV    -39.41mA   -24.7mA    -62.22mA
-423mV    -32.02mA   -19.39mA   -52.05mA
95mV      5.729mA    2.992mA    10.49mA
354mV     15.29mA    7.674mA    28.14mA
761mV     19.19mA    9.392mA    35.13mA
1.649V    21.15mA    10.51mA    38.38mA
2.019V    25.42mA    15.26mA    39.86mA
2.167V    29.78mA    18.68mA    44.57mA
2.4V      38.61mA    25.27mA    56.96mA
[Pullup]
|Voltage   I(typ)   I(min)   I(max)
-1.2V     83.3mA     59.33mA    129.8mA
-893mV    59.32mA    41.69mA    92.9mA
-560mV    35.41mA    24.12mA    58.49mA
-338mV    19.19mA    13.06mA    32.47mA
-190mV    9.687mA    6.463mA    16.55mA
-79mV     3.668mA    2.398mA    6.116mA
32mV      -1.332mA   -852.4uA   -2.917mA
143mV     -5.255mA   -3.327mA   -10.26mA
254mV     -8.11mA    -5.063mA   -15.86mA
402mV     -10.32mA   -6.287mA   -20.71mA
587mV     -11.14mA   -6.66mA    -23.11mA
2.4V      -13.01mA   -7.655mA   -27.74mA
[GND_clamp]
|Voltage   I(typ)   I(min)   I(max)
-1.2V     -586.8mA   -561.7mA   -640.4mA
-1.075V   -375.3mA   -403.2mA   -342.9mA
-1V       -256.8mA   -312.4mA   -188.9mA
-950mV    -184.3mA   -254.5mA   -114.1mA
-925mV    -151.1mA   -226.6mA   -91.32mA
-875mV    -94.01mA   -173.6mA   -70.06mA
-800mV    -43.56mA   -102.9mA   -56.11mA
-725mV    -26.45mA   -48.06mA   -41.65mA
-650mV    -16.55mA   -16.39mA   -27.24mA
-575mV    -8.728mA   -5.059mA   -14.79mA
-375mV    -266.5uA   -129.3uA   -404.6uA
1.2V      0A         0A         0A
[POWER_clamp]
|Voltage   I(typ)   I(min)   I(max)
-1.2V     9.358mA    4.601mA    22.1mA
-950mV    6.537mA    3.101mA    16.64mA
-825mV    5.08mA     2.355mA    13.4mA
-775mV    4.466mA    2.06mA     11.6mA
-650mV    2.734mA    1.335mA    5.647mA
-600mV    1.907mA    1.053mA    3.642mA
-550mV    1.113mA    778.7uA    2.069mA
-525mV    798uA      647.5uA    1.472mA
-475mV    381.7uA    406uA      682.4uA
-425mV    196.4uA    214.2uA    354.3uA
-350mV    117.6uA    72.69uA    251.1uA
1.2V      0A         0A         29.9uA
[Ramp]
| variable   typ   min   max
dV/dt_r   0.334/0.471n   0.203/0.625n   0.557/0.248n
dV/dt_f   0.483/0.343n   0.277/0.601n   0.627/0.159n
R_load = 50.000
[Rising Waveform]
R_fixture= 50.000
V_fixture= 0.0
V_fixture_min= 0.0
V_fixture_max= 0.0
|time   V(typ)   V(min)   V(max)
0s        2.225nV    32.56nV    936.2pV
1.027ns   21.18uV    6.474uV    -33.26mV
1.242ns   65.73uV    6.474uV    546.6mV
1.399ns   -37.61uV   6.474uV    764.2mV
2.133ns   -35.02mV   31.33uV    908.8mV
2.713ns   421.9mV    -253.6uV   921.5mV
3.572ns   523.9mV    -2.586mV   926.6mV
4.407ns   543.8mV    -13.17mV   927.5mV
6.23ns    555.2mV    322mV      927.8mV
20ns      557.4mV    339mV      927.8mV
[Rising Waveform]
R_fixture= 50.000
V_fixture= 1.200
V_fixture_min= 1.140
V_fixture_max= 1.260
|time   V(typ)   V(min)   V(max)
0s        392.9mV    677.3mV    216.8mV
929ps     392.9mV    677.4mV    210.4mV
1.185ns   392.7mV    677.3mV    1.108V
1.427ns   394mV      677.3mV    1.241V
1.894ns   382.4mV    677.2mV    1.256V
2.336ns   1.056V     677.2mV    1.26V
2.696ns   1.182V     679mV      1.261V
3.591ns   1.195V     644mV      1.262V
5.076ns   1.198V     1.13V      1.262V
20ns      1.198V     1.139V     1.262V
[Falling Waveform]
R_fixture= 50.000
V_fixture= 1.200
V_fixture_min= 1.140
V_fixture_max= 1.260
|time   V(typ)   V(min)   V(max)
0s        1.198V     1.139V     1.262V
1.036ns   1.198V     1.139V     1.319V
1.32ns    1.198V     1.139V     344.1mV
1.769ns   1.198V     1.139V     228.7mV
2.218ns   1.233V     1.139V     221.9mV
2.724ns   533.5mV    1.139V     218.8mV
3.311ns   412.1mV    1.14V      217.3mV
4.547ns   396.2mV    1.157V     216.9mV
6.231ns   393.3mV    693mV      216.9mV
20ns      392.9mV    677.3mV    216.8mV
[Falling Waveform]
R_fixture= 50.000
V_fixture= 0.0
V_fixture_min= 0.0
V_fixture_max= 0.0
|time   V(typ)   V(min)   V(max)
0s        557.4mV    339mV      927.8mV
943ps     557.5mV    339.1mV    924.1mV
1.028ns   557.5mV    339.1mV    746.6mV
1.174ns   557.5mV    339.1mV    111.5mV
1.338ns   557.5mV    339.1mV    15.78mV
1.939ns   550.9mV    339mV      3.129mV
2.575ns   13.22mV    339.1mV    768.4uV
3.855ns   1.165mV    337.8mV    56.11uV
5.211ns   192.9uV    4.605mV    21.05uV
20ns      -538.9nV   -1.128uV   -614.9nV
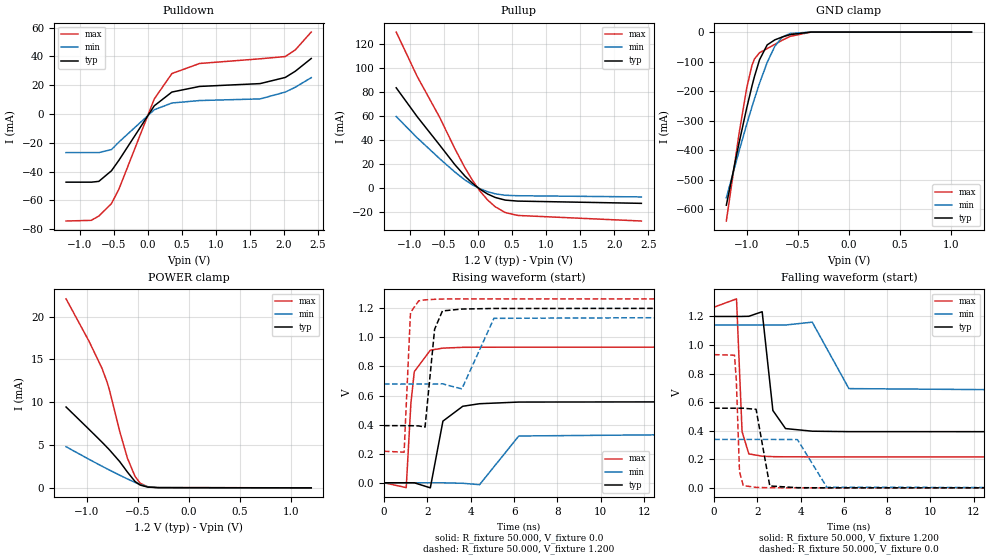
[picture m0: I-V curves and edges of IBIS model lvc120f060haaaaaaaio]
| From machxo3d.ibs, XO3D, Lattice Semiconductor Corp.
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|   Model lvc120f060haaaaaaaio
[Model] lvc120f060haaaaaaaio
Model_type I/O
Polarity   Non-Inverting
Enable   Active-Low
Vinl =  0.420V
Vinh =  0.780V
Vmeas =  0.600V
Cref =  0.0F
Rref =  1.000M
Vref =  0.0V
C_comp   4.200pF   3.800pF   7.500pF
[Temperature Range]   25.000   0.105k   -40.000
[Voltage Range]   1.200V   1.140V   1.260V
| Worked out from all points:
|   slope of the pulldown table from 0 to 0.18 V, typ, clamps not added: 18.4 ohm
|   slope of the pullup table from 0 to 0.18 V, typ, clamps not added: 28.4 ohm
|   GND clamp passes 1 mA (typ) near -0.44 V on its own axis
|   POWER clamp passes 1 mA (typ) near -0.55 V on its own axis
|   rising waveform, R_fixture 50.000, V_fixture 0.0: 20-80 % time 469ps typ, 625ps min, 252ps max; typ from 0 V to 0.557 V
|   rising waveform, R_fixture 50.000, V_fixture 1.200: 20-80 % time 304ps typ, 477ps min, 142ps max; typ from 0.393 V to 1.2 V
|   falling waveform, R_fixture 50.000, V_fixture 1.200: 20-80 % time 347ps typ, 589ps min, 160ps max; typ from 1.2 V to 0.393 V
|   falling waveform, R_fixture 50.000, V_fixture 0.0: 20-80 % time 277ps typ, 492ps min, 120ps max; typ from 0.557 V to 0 V
[Pulldown]
|Voltage   I(typ)   I(min)   I(max)
-1.2V     -47.32mA   -26.76mA   -74.29mA
-830mV    -47.32mA   -26.76mA   -73.83mA
-719mV    -46.75mA   -26.76mA   -70.83mA
-534mV    -39.41mA   -24.7mA    -62.22mA
-423mV    -32.02mA   -19.39mA   -52.05mA
95mV      5.729mA    2.992mA    10.49mA
354mV     15.29mA    7.674mA    28.14mA
761mV     19.19mA    9.392mA    35.13mA
1.649V    21.15mA    10.51mA    38.38mA
2.019V    25.43mA    15.27mA    39.95mA
2.167V    29.78mA    18.68mA    44.59mA
2.4V      38.6mA     25.28mA    56.97mA
[Pullup]
|Voltage   I(typ)   I(min)   I(max)
-1.2V     83.3mA     59.35mA    129.8mA
-893mV    59.32mA    41.69mA    92.93mA
-560mV    35.41mA    24.12mA    58.49mA
-338mV    19.19mA    13.06mA    32.47mA
-190mV    9.687mA    6.463mA    16.55mA
-79mV     3.668mA    2.398mA    6.116mA
32mV      -1.332mA   -852.4uA   -2.917mA
143mV     -5.255mA   -3.327mA   -10.26mA
254mV     -8.11mA    -5.063mA   -15.86mA
402mV     -10.32mA   -6.287mA   -20.71mA
587mV     -11.14mA   -6.66mA    -23.11mA
2.4V      -13.01mA   -7.655mA   -27.74mA
[GND_clamp]
|Voltage   I(typ)   I(min)   I(max)
-1.2V     -586.8mA   -561.7mA   -640.4mA
-1.075V   -375.3mA   -403.2mA   -342.9mA
-1V       -256.8mA   -312.4mA   -188.9mA
-950mV    -184.3mA   -254.5mA   -114.1mA
-925mV    -151.1mA   -226.6mA   -91.32mA
-875mV    -94.01mA   -173.6mA   -70.06mA
-800mV    -43.56mA   -102.9mA   -56.11mA
-725mV    -26.45mA   -48.06mA   -41.65mA
-650mV    -16.55mA   -16.39mA   -27.24mA
-575mV    -8.728mA   -5.059mA   -14.79mA
-375mV    -266.5uA   -129.3uA   -404.6uA
1.2V      -42.59nA   0A         -5.33uA
[POWER_clamp]
|Voltage   I(typ)   I(min)   I(max)
-1.2V     9.441mA    4.803mA    22.07mA
-975mV    6.83mA     3.329mA    17.11mA
-850mV    5.356mA    2.536mA    14mA
-800mV    4.744mA    2.228mA    12.4mA
-775mV    4.43mA     2.076mA    11.41mA
-675mV    3.065mA    1.478mA    6.596mA
-600mV    1.851mA    1.044mA    3.486mA
-525mV    744.7uA    632.6uA    1.337mA
-475mV    325.6uA    388.1uA    543.5uA
-400mV    86.39uA    124.7uA    120.1uA
-300mV    23.03uA    20.03uA    34.62uA
1.2V      0A         0A         0A
[Ramp]
| variable   typ   min   max
dV/dt_r   0.334/0.471n   0.203/0.625n   0.560/0.252n
dV/dt_f   0.484/0.347n   0.277/0.596n   0.629/0.161n
R_load = 50.000
[Rising Waveform]
R_fixture= 50.000
V_fixture= 0.0
V_fixture_min= 0.0
V_fixture_max= 0.0
|time   V(typ)   V(min)   V(max)
0s        2.225nV    32.56nV    936.2pV
1.027ns   -6.799uV   6.466uV    -33.26mV
1.242ns   24.62uV    6.466uV    546.6mV
1.399ns   -114.2uV   6.466uV    764.2mV
2.138ns   -34.92mV   31.33uV    911.9mV
2.719ns   424mV      -253.6uV   926.2mV
3.633ns   526.1mV    -3.507mV   931.7mV
4.407ns   543.8mV    -13.17mV   932.3mV
6.217ns   555.2mV    321.8mV    932.6mV
20ns      557.4mV    339mV      932.6mV
[Rising Waveform]
R_fixture= 50.000
V_fixture= 1.200
V_fixture_min= 1.140
V_fixture_max= 1.260
|time   V(typ)   V(min)   V(max)
0s        392.9mV    679.1mV    216.8mV
929ps     392.9mV    679.1mV    210.4mV
1.224ns   392.8mV    679.1mV    1.171V
1.601ns   391.1mV    679.1mV    1.251V
1.894ns   382.4mV    679mV      1.258V
2.336ns   1.056V     679mV      1.262V
2.696ns   1.182V     680.7mV    1.264V
3.591ns   1.195V     645.8mV    1.265V
5.071ns   1.199V     1.131V     1.265V
20ns      1.2V       1.14V      1.265V
[Falling Waveform]
R_fixture= 50.000
V_fixture= 1.200
V_fixture_min= 1.140
V_fixture_max= 1.260
|time   V(typ)   V(min)   V(max)
0s        1.2V       1.14V      1.265V
1.037ns   1.2V       1.14V      1.323V
1.294ns   1.2V       1.14V      393.7mV
1.606ns   1.201V     1.14V      237.7mV
2.223ns   1.233V     1.14V      221.7mV
2.718ns   541.5mV    1.14V      218.4mV
3.302ns   415mV      1.14V      217.2mV
4.537ns   396.6mV    1.16V      216.9mV
6.232ns   393.5mV    694.8mV    216.8mV
20ns      392.9mV    679.1mV    216.8mV
[Falling Waveform]
R_fixture= 50.000
V_fixture= 0.0
V_fixture_min= 0.0
V_fixture_max= 0.0
|time   V(typ)   V(min)   V(max)
0s        557.4mV    339mV      932.6mV
944ps     557.5mV    339.1mV    928.6mV
1.028ns   557.5mV    339.1mV    753.9mV
1.175ns   557.5mV    339.1mV    113.8mV
1.347ns   557.5mV    339.1mV    15.92mV
1.942ns   549.8mV    339mV      3.126mV
2.575ns   13.22mV    339.1mV    803.1uV
3.855ns   1.165mV    337.8mV    69.97uV
5.211ns   192.9uV    4.605mV    29.57uV
20ns      -538.9nV   -1.128uV   -204.1nV
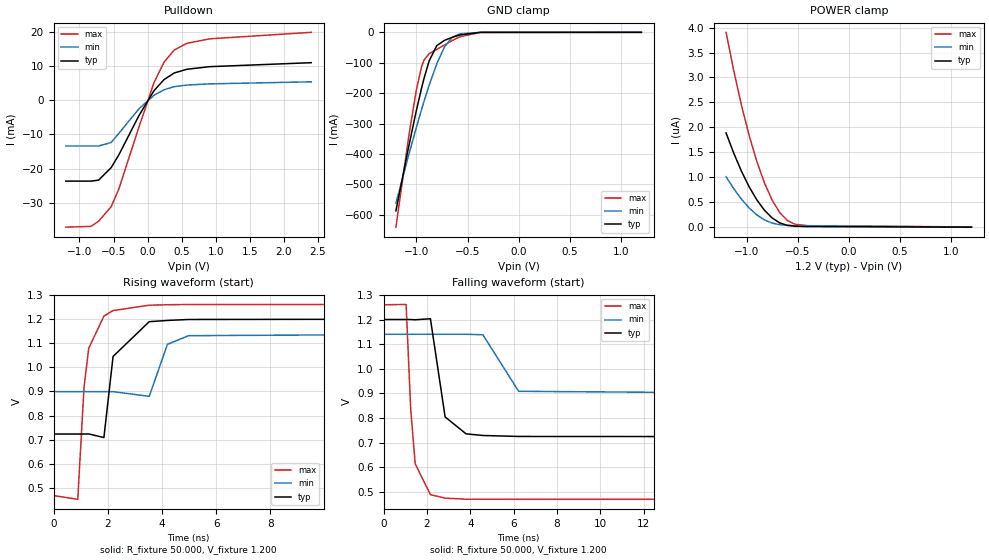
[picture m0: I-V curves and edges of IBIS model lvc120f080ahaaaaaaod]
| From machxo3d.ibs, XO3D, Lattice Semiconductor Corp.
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|   Model lvc120f080ahaaaaaaod
[Model] lvc120f080ahaaaaaaod
Model_type I/O_open_drain
Polarity   Non-Inverting
Enable   Active-Low
Vinl =  0.420V
Vinh =  0.780V
Vmeas =  0.600V
Cref =  0.0F
Rref = 10.00k
Vref = 1.20V
C_comp   4.200pF   3.800pF   7.500pF
[Temperature Range]   25.000   0.105k   -40.000
[Voltage Range]   1.200V   1.140V   1.260V
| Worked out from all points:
|   slope of the pulldown table from 0 to 0.18 V, typ, clamps not added: 36.7 ohm
|   GND clamp passes 1 mA (typ) near -0.44 V on its own axis
|   rising waveform, R_fixture 50.000, V_fixture 1.200: 20-80 % time 359ps typ, 408ps min, 350ps max; typ from 0.724 V to 1.2 V
|   falling waveform, R_fixture 50.000, V_fixture 1.200: 20-80 % time 438ps typ, 632ps min, 307ps max; typ from 1.2 V to 0.724 V
[Pulldown]
|Voltage   I(typ)   I(min)   I(max)
-1.2V     -23.66mA   -13.38mA   -37.14mA
-830mV    -23.66mA   -13.38mA   -36.91mA
-719mV    -23.37mA   -13.38mA   -35.42mA
-534mV    -19.7mA    -12.35mA   -31.11mA
-423mV    -16.01mA   -9.695mA   -26.02mA
-127mV    -4.473mA   -2.488mA   -7.831mA
95mV      2.865mA    1.496mA    5.244mA
243mV     6.106mA    3.121mA    11.23mA
391mV     8.008mA    3.999mA    14.74mA
576mV     9.093mA    4.47mA     16.69mA
909mV     9.852mA    4.817mA    18mA
2.4V      11.02mA    5.419mA    19.91mA
[GND_clamp]
|Voltage   I(typ)   I(min)   I(max)
-1.2V     -586.8mA   -561.6mA   -640.4mA
-1.075V   -375.3mA   -403.2mA   -342.9mA
-1V       -256.8mA   -312.3mA   -188.8mA
-950mV    -184.3mA   -254.5mA   -114.1mA
-925mV    -151.1mA   -226.6mA   -91.28mA
-875mV    -93.98mA   -173.6mA   -70.02mA
-800mV    -43.52mA   -102.9mA   -56.06mA
-725mV    -26.41mA   -48.03mA   -41.59mA
-650mV    -16.51mA   -16.35mA   -27.18mA
-575mV    -8.675mA   -5.014mA   -14.71mA
-375mV    -184.4uA   -82.53uA   -274.8uA
1.2V      0A         0A         0A
[POWER_clamp]
|Voltage   I(typ)   I(min)   I(max)
-1.2V     1.889uA    1.011uA    3.905uA
-1.125V   1.485uA    772.5nA    3.141uA
-1.05V    1.124uA    563.1nA    2.451uA
-975mV    812.1nA    387.4nA    1.845uA
-900mV    550.1nA    247.5nA    1.324uA
-825mV    340.1nA    145.7nA    890.5nA
-750mV    184.9nA    81.62nA    545.5nA
-675mV    85.57nA    49.09nA    292.2nA
-600mV    35.85nA    35.98nA    132.8nA
-525mV    17.84nA    31.28nA    57.78nA
-400mV    11.63nA    28.62nA    28.93nA
1.2V      0A         0A         3.813nA
[Ramp]
| variable   typ   min   max
dV/dt_r   0.286/0.358n   0.144/0.410n   0.476/0.351n
dV/dt_f   0.286/0.431n   0.144/0.601n   0.476/0.303n
R_load = 50.000
[Rising Waveform]
R_fixture= 50.000
V_fixture= 1.200
V_fixture_min= 1.140
V_fixture_max= 1.260
|time   V(typ)   V(min)   V(max)
0s        724mV      899.5mV    469.4mV
894ps     724mV      899.5mV    453.7mV
1.125ns   723.9mV    899.5mV    916mV
1.299ns   724.4mV    899.5mV    1.079V
1.859ns   709.4mV    899.3mV    1.212V
2.197ns   1.045V     899.4mV    1.235V
3.532ns   1.189V     879.9mV    1.257V
4.202ns   1.194V     1.095V     1.259V
4.981ns   1.198V     1.131V     1.26V
20ns      1.2V       1.14V      1.26V
[Falling Waveform]
R_fixture= 50.000
V_fixture= 1.200
V_fixture_min= 1.140
V_fixture_max= 1.260
|time   V(typ)   V(min)   V(max)
0s        1.2V       1.14V      1.26V
1.036ns   1.2V       1.14V      1.261V
1.248ns   1.2V       1.14V      835.7mV
1.456ns   1.199V     1.14V      613.5mV
2.158ns   1.203V     1.14V      488.2mV
2.836ns   804.1mV    1.14V      474.2mV
3.803ns   735.4mV    1.14V      469.8mV
4.579ns   728.7mV    1.138V     469.7mV
6.228ns   724.8mV    908.3mV    469.4mV
20ns      724mV      899.5mV    469.3mV
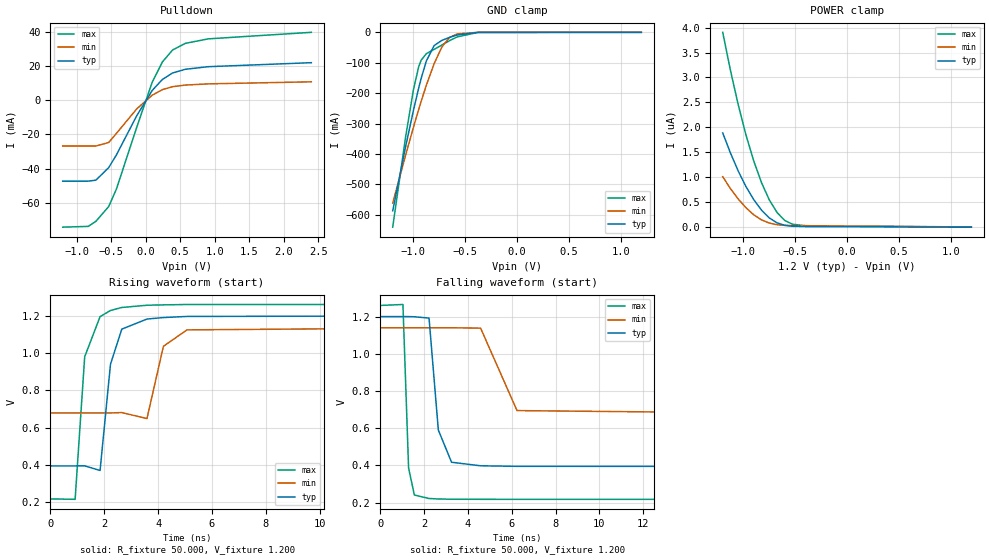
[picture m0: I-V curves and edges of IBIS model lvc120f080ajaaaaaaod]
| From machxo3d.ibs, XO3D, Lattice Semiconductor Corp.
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|   Model lvc120f080ajaaaaaaod
[Model] lvc120f080ajaaaaaaod
Model_type I/O_open_drain
Polarity   Non-Inverting
Enable   Active-Low
Vinl =  0.420V
Vinh =  0.780V
Vmeas =  0.600V
Cref =  0.0F
Rref = 10.00k
Vref = 1.20V
C_comp   4.200pF   3.800pF   7.500pF
[Temperature Range]   25.000   0.105k   -40.000
[Voltage Range]   1.200V   1.140V   1.260V
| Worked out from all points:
|   slope of the pulldown table from 0 to 0.18 V, typ, clamps not added: 18.4 ohm
|   GND clamp passes 1 mA (typ) near -0.44 V on its own axis
|   rising waveform, R_fixture 50.000, V_fixture 1.200: 20-80 % time 360ps typ, 412ps min, 353ps max; typ from 0.395 V to 1.2 V
|   falling waveform, R_fixture 50.000, V_fixture 1.200: 20-80 % time 355ps typ, 605ps min, 164ps max; typ from 1.2 V to 0.395 V
[Pulldown]
|Voltage   I(typ)   I(min)   I(max)
-1.2V     -47.32mA   -26.76mA   -74.28mA
-830mV    -47.32mA   -26.76mA   -73.83mA
-719mV    -46.75mA   -26.76mA   -70.83mA
-534mV    -39.41mA   -24.7mA    -62.22mA
-423mV    -32.02mA   -19.39mA   -52.05mA
-127mV    -8.946mA   -4.976mA   -15.66mA
95mV      5.729mA    2.992mA    10.49mA
243mV     12.21mA    6.242mA    22.45mA
391mV     16.02mA    7.998mA    29.47mA
576mV     18.19mA    8.94mA     33.37mA
909mV     19.7mA     9.634mA    36mA
2.4V      22.04mA    10.84mA    39.82mA
[GND_clamp]
|Voltage   I(typ)   I(min)   I(max)
-1.2V     -586.8mA   -561.6mA   -640.4mA
-1.075V   -375.3mA   -403.2mA   -342.9mA
-1V       -256.8mA   -312.3mA   -188.8mA
-950mV    -184.3mA   -254.5mA   -114.1mA
-925mV    -151.1mA   -226.6mA   -91.28mA
-875mV    -93.98mA   -173.6mA   -70.02mA
-800mV    -43.52mA   -102.9mA   -56.06mA
-725mV    -26.41mA   -48.03mA   -41.59mA
-650mV    -16.51mA   -16.35mA   -27.18mA
-575mV    -8.675mA   -5.014mA   -14.71mA
-375mV    -184.4uA   -82.53uA   -274.8uA
1.2V      0A         0A         0A
[POWER_clamp]
|Voltage   I(typ)   I(min)   I(max)
-1.2V     1.889uA    1.011uA    3.905uA
-1.125V   1.485uA    772.5nA    3.141uA
-1.05V    1.124uA    563.1nA    2.451uA
-975mV    812.1nA    387.4nA    1.845uA
-900mV    550.1nA    247.5nA    1.324uA
-825mV    340.1nA    145.7nA    890.5nA
-750mV    184.9nA    81.62nA    545.5nA
-675mV    85.57nA    49.09nA    292.2nA
-600mV    35.85nA    35.97nA    132.8nA
-525mV    17.85nA    31.27nA    57.79nA
-400mV    11.64nA    28.61nA    28.94nA
1.2V      0A         0A         3.813nA
[Ramp]
| variable   typ   min   max
dV/dt_r   0.483/0.357n   0.277/0.413n   0.628/0.351n
dV/dt_f   0.483/0.352n   0.277/0.608n   0.628/0.164n
R_load = 50.000
[Rising Waveform]
R_fixture= 50.000
V_fixture= 1.200
V_fixture_min= 1.140
V_fixture_max= 1.260
|time   V(typ)   V(min)   V(max)
0s        394.7mV    678.9mV    217.9mV
922ps     394.7mV    678.9mV    215.6mV
1.277ns   395mV      678.9mV    979.7mV
1.848ns   370.3mV    678.8mV    1.195V
2.234ns   939.7mV    678.6mV    1.228V
2.654ns   1.128V     680.6mV    1.244V
3.588ns   1.182V     648.6mV    1.256V
4.198ns   1.19V      1.036V     1.258V
5.074ns   1.196V     1.124V     1.26V
20ns      1.2V       1.14V      1.26V
[Falling Waveform]
R_fixture= 50.000
V_fixture= 1.200
V_fixture_min= 1.140
V_fixture_max= 1.260
|time   V(typ)   V(min)   V(max)
0s        1.2V       1.14V      1.26V
1.034ns   1.2V       1.14V      1.265V
1.292ns   1.2V       1.14V      386.6mV
1.556ns   1.199V     1.14V      241.1mV
2.225ns   1.192V     1.14V      222.4mV
2.65ns    590.2mV    1.14V      219.8mV
3.253ns   417.3mV    1.14V      218.4mV
4.579ns   398.1mV    1.138V     218mV
6.241ns   395.3mV    694.8mV    217.9mV
20ns      394.7mV    678.9mV    217.9mV
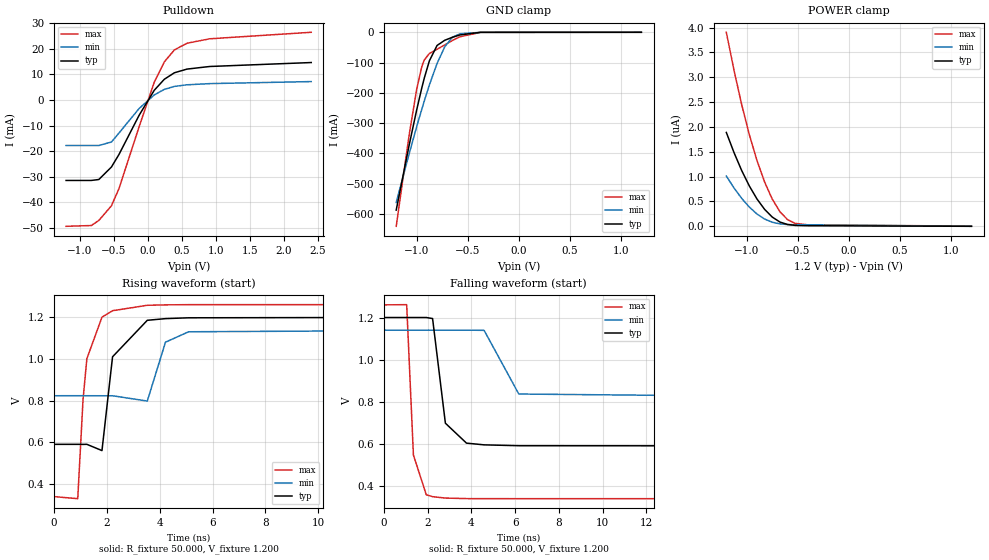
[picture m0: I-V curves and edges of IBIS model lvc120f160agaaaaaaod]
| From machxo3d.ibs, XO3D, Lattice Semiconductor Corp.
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|   Model lvc120f160agaaaaaaod
[Model] lvc120f160agaaaaaaod
Model_type I/O_open_drain
Polarity   Non-Inverting
Enable   Active-Low
Vinl =  0.420V
Vinh =  0.780V
Vmeas =  0.600V
Cref =  0.0F
Rref = 10.00k
Vref = 1.20V
C_comp   4.200pF   3.800pF   7.500pF
[Temperature Range]   25.000   0.105k   -40.000
[Voltage Range]   1.200V   1.140V   1.260V
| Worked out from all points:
|   slope of the pulldown table from 0 to 0.18 V, typ, clamps not added: 27.5 ohm
|   GND clamp passes 1 mA (typ) near -0.44 V on its own axis
|   rising waveform, R_fixture 50.000, V_fixture 1.200: 20-80 % time 360ps typ, 412ps min, 350ps max; typ from 0.59 V to 1.2 V
|   falling waveform, R_fixture 50.000, V_fixture 1.200: 20-80 % time 422ps typ, 637ps min, 246ps max; typ from 1.2 V to 0.59 V
[Pulldown]
|Voltage   I(typ)   I(min)   I(max)
-1.2V     -31.54mA   -17.84mA   -49.52mA
-830mV    -31.54mA   -17.84mA   -49.22mA
-719mV    -31.17mA   -17.84mA   -47.22mA
-534mV    -26.27mA   -16.47mA   -41.48mA
-423mV    -21.34mA   -12.93mA   -34.7mA
-127mV    -5.964mA   -3.318mA   -10.44mA
95mV      3.82mA     1.995mA    6.992mA
243mV     8.142mA    4.162mA    14.97mA
391mV     10.68mA    5.332mA    19.65mA
576mV     12.12mA    5.96mA     22.25mA
909mV     13.14mA    6.423mA    24mA
2.4V      14.69mA    7.225mA    26.55mA
[GND_clamp]
|Voltage   I(typ)   I(min)   I(max)
-1.2V     -586.8mA   -561.6mA   -640.3mA
-1.075V   -375.3mA   -403.2mA   -342.9mA
-1V       -256.8mA   -312.3mA   -188.8mA
-950mV    -184.3mA   -254.5mA   -114.1mA
-925mV    -151.1mA   -226.6mA   -91.26mA
-875mV    -93.95mA   -173.6mA   -69.99mA
-800mV    -43.5mA    -102.9mA   -56.04mA
-725mV    -26.4mA    -48.03mA   -41.57mA
-650mV    -16.5mA    -16.35mA   -27.16mA
-575mV    -8.667mA   -5.012mA   -14.69mA
-375mV    -183.5uA   -82.46uA   -270.8uA
1.2V      0A         0A         0A
[POWER_clamp]
|Voltage   I(typ)   I(min)   I(max)
-1.2V     1.889uA    1.011uA    3.905uA
-1.125V   1.485uA    772.5nA    3.141uA
-1.05V    1.124uA    563.1nA    2.451uA
-975mV    812.1nA    387.4nA    1.845uA
-900mV    550.1nA    247.5nA    1.324uA
-825mV    340.1nA    145.7nA    890.6nA
-750mV    184.9nA    81.62nA    545.5nA
-675mV    85.59nA    49.09nA    292.2nA
-600mV    35.87nA    35.97nA    132.8nA
-525mV    17.86nA    31.27nA    57.82nA
-400mV    11.65nA    28.61nA    28.97nA
1.2V      0A         0A         3.808nA
[Ramp]
| variable   typ   min   max
dV/dt_r   0.366/0.358n   0.190/0.413n   0.554/0.354n
dV/dt_f   0.366/0.417n   0.190/0.607n   0.554/0.245n
R_load = 50.000
[Rising Waveform]
R_fixture= 50.000
V_fixture= 1.200
V_fixture_min= 1.140
V_fixture_max= 1.260
|time   V(typ)   V(min)   V(max)
0s        590.1mV    823.2mV    339.5mV
904ps     590.1mV    823.3mV    329.4mV
1.105ns   589.8mV    823.2mV    805.9mV
1.249ns   590.2mV    823.2mV    1.001V
1.82ns    560.1mV    823.1mV    1.2V
2.22ns    1.01V      823.1mV    1.231V
3.533ns   1.185V     797.6mV    1.257V
4.22ns    1.193V     1.08V      1.259V
5.097ns   1.197V     1.13V      1.26V
20ns      1.2V       1.14V      1.26V
[Falling Waveform]
R_fixture= 50.000
V_fixture= 1.200
V_fixture_min= 1.140
V_fixture_max= 1.260
|time   V(typ)   V(min)   V(max)
0s        1.2V       1.14V      1.26V
1.039ns   1.2V       1.14V      1.261V
1.347ns   1.2V       1.14V      546.8mV
1.935ns   1.2V       1.14V      357.9mV
2.223ns   1.195V     1.14V      349mV
2.808ns   697.9mV    1.14V      342.3mV
3.773ns   603.3mV    1.14V      339.8mV
4.578ns   595.1mV    1.139V     339.6mV
6.163ns   591mV      836.5mV    339.4mV
20ns      590.1mV    823.2mV    339.4mV
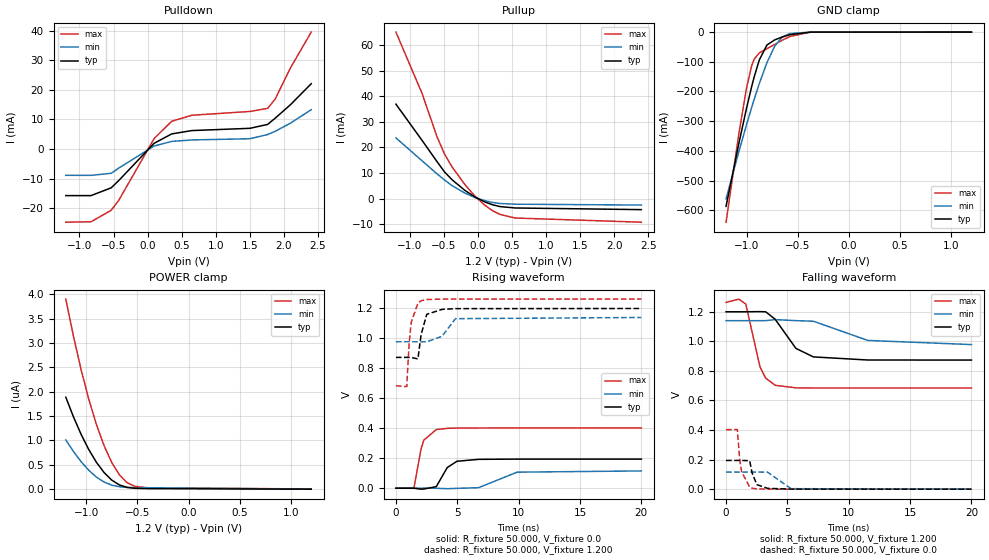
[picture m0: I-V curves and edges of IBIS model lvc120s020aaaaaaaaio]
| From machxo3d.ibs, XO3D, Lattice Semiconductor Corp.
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|   Model lvc120s020aaaaaaaaio
[Model] lvc120s020aaaaaaaaio
Model_type I/O
Polarity   Non-Inverting
Enable   Active-Low
Vinl =  0.420V
Vinh =  0.780V
Vmeas =  0.600V
Cref =  0.0F
Rref =  1.000M
Vref =  0.0V
C_comp   4.200pF   3.800pF   7.500pF
[Temperature Range]   25.000   0.105k   -40.000
[Voltage Range]   1.200V   1.140V   1.260V
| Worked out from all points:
|   slope of the pulldown table from 0 to 0.18 V, typ, clamps not added: 55.1 ohm
|   slope of the pullup table from 0 to 0.18 V, typ, clamps not added: 85.3 ohm
|   GND clamp passes 1 mA (typ) near -0.44 V on its own axis
|   rising waveform, R_fixture 50.000, V_fixture 0.0: 20-80 % time 915ps typ, 1.64ns min, 587ps max; typ from 0 V to 0.194 V
|   rising waveform, R_fixture 50.000, V_fixture 1.200: 20-80 % time 367ps typ, 416ps min, 385ps max; typ from 0.873 V to 1.2 V
|   falling waveform, R_fixture 50.000, V_fixture 1.200: 20-80 % time 1.85ns typ, 3.11ns min, 980ps max; typ from 1.2 V to 0.873 V
|   falling waveform, R_fixture 50.000, V_fixture 0.0: 20-80 % time 407ps typ, 468ps min, 385ps max; typ from 0.194 V to 0 V
[Pulldown]
|Voltage   I(typ)   I(min)   I(max)
-1.2V     -15.77mA   -8.921mA   -24.76mA
-830mV    -15.77mA   -8.921mA   -24.61mA
-534mV    -13.14mA   -8.234mA   -20.74mA
-423mV    -10.67mA   -6.463mA   -17.35mA
95mV      1.91mA     997.3uA    3.496mA
354mV     5.095mA    2.558mA    9.38mA
650mV     6.221mA    3.05mA     11.4mA
1.501V    6.983mA    3.464mA    12.68mA
1.76V     8.298mA    4.874mA    13.72mA
1.871V    10.4mA     5.962mA    16.85mA
2.093V    14.91mA    8.691mA    27.31mA
2.4V      22.06mA    13.29mA    39.52mA
[Pullup]
|Voltage   I(typ)   I(min)   I(max)
-1.2V     36.91mA    23.72mA    65.09mA
-819mV    22.83mA    14.81mA    41.26mA
-597mV    14.43mA    9.66mA     24.15mA
-486mV    10.38mA    7.228mA    17.33mA
-375mV    7.309mA    5.026mA    12.31mA
-190mV    3.229mA    2.154mA    5.518mA
-42mV     628.1uA    407.3uA    979.6uA
106mV     -1.356mA   -861.5uA   -2.669mA
217mV     -2.425mA   -1.522mA   -4.729mA
328mV     -3.145mA   -1.941mA   -6.218mA
550mV     -3.688mA   -2.208mA   -7.621mA
2.4V      -4.336mA   -2.551mA   -9.246mA
[GND_clamp]
|Voltage   I(typ)   I(min)   I(max)
-1.2V     -586.8mA   -561.6mA   -640.3mA
-1.075V   -375.3mA   -403.2mA   -342.9mA
-1V       -256.8mA   -312.3mA   -188.8mA
-950mV    -184.3mA   -254.5mA   -114.1mA
-925mV    -151.1mA   -226.6mA   -91.26mA
-875mV    -93.95mA   -173.6mA   -69.99mA
-800mV    -43.5mA    -102.9mA   -56.04mA
-725mV    -26.4mA    -48.03mA   -41.57mA
-650mV    -16.5mA    -16.35mA   -27.16mA
-575mV    -8.667mA   -5.012mA   -14.69mA
-375mV    -183.5uA   -82.46uA   -270.8uA
1.2V      0A         0A         0A
[POWER_clamp]
|Voltage   I(typ)   I(min)   I(max)
-1.2V     1.889uA    1.011uA    3.905uA
-1.125V   1.485uA    772.5nA    3.141uA
-1.05V    1.124uA    563.1nA    2.451uA
-975mV    812.1nA    387.4nA    1.845uA
-900mV    550.1nA    247.6nA    1.324uA
-825mV    340.1nA    145.7nA    890.5nA
-750mV    184.9nA    81.65nA    545.5nA
-675mV    85.57nA    49.12nA    292.2nA
-600mV    35.85nA    36nA       132.8nA
-525mV    17.85nA    31.3nA     57.78nA
-400mV    11.64nA    28.64nA    28.94nA
1.2V      0A         0A         3.808nA
[Ramp]
| variable   typ   min   max
dV/dt_r   0.117/0.888n   69.290m/1.663n   0.241/0.593n
dV/dt_f   0.196/1.802n   97.146m/3.072n   0.346/0.976n
R_load = 50.000
[Rising Waveform]
R_fixture= 50.000
V_fixture= 0.0
V_fixture_min= 0.0
V_fixture_max= 0.0
|time   V(typ)   V(min)   V(max)
0s        4.736nV    57.27nV    2.383nV
1.466ns   61.96uV    14.48uV    -365.1uV
2.035ns   -6.349mV   66.89uV    257.2mV
2.265ns   -5.429mV   193.7uV    320.3mV
3.286ns   10.34mV    -410.6uV   391.7mV
4.183ns   138mV      -3.359mV   399.7mV
4.97ns    179.9mV    -865.6uV   401.6mV
6.735ns   192.8mV    3.499mV    402.2mV
9.876ns   194.3mV    107.2mV    402.3mV
20ns      194.3mV    115.5mV    402.3mV
[Rising Waveform]
R_fixture= 50.000
V_fixture= 1.200
V_fixture_min= 1.140
V_fixture_max= 1.260
|time   V(typ)   V(min)   V(max)
0s        873.4mV    977.9mV    684.3mV
883ps     873.4mV    977.9mV    678.1mV
1.076ns   873.3mV    977.9mV    968.5mV
1.251ns   873.3mV    977.9mV    1.108V
1.792ns   863.1mV    977.8mV    1.236V
2.053ns   1.026V     977.7mV    1.252V
2.512ns   1.161V     977.8mV    1.26V
3.75ns    1.194V     1.014V     1.263V
4.852ns   1.199V     1.132V     1.263V
20ns      1.2V       1.14V      1.263V
[Falling Waveform]
R_fixture= 50.000
V_fixture= 1.200
V_fixture_min= 1.140
V_fixture_max= 1.260
|time   V(typ)   V(min)   V(max)
0s        1.2V       1.14V      1.263V
1.04ns    1.2V       1.14V      1.286V
1.61ns    1.2V       1.14V      1.252V
2.762ns   1.201V     1.14V      828.1mV
3.226ns   1.2V       1.14V      751.7mV
4.006ns   1.149V     1.147V     702.6mV
5.693ns   952.3mV    1.14V      685.4mV
7.117ns   894.7mV    1.136V     684.5mV
11.56ns   873.7mV    1.006V     684.3mV
20ns      873.4mV    978.1mV    684.3mV
[Falling Waveform]
R_fixture= 50.000
V_fixture= 0.0
V_fixture_min= 0.0
V_fixture_max= 0.0
|time   V(typ)   V(min)   V(max)
0s        194.3mV    115.5mV    402.3mV
915ps     194.3mV    115.5mV    403.6mV
1.109ns   194.3mV    115.5mV    206.7mV
1.262ns   194.3mV    115.5mV    118.3mV
1.925ns   192.8mV    115.5mV    14.21mV
2.123ns   110mV      115.5mV    6.59mV
2.504ns   31.01mV    115.5mV    2.257mV
3.378ns   5.437mV    115.1mV    386.5uV
5.299ns   533.6uV    3.325mV    15.01uV
20ns      12.65nV    911.7nV    3.151nV
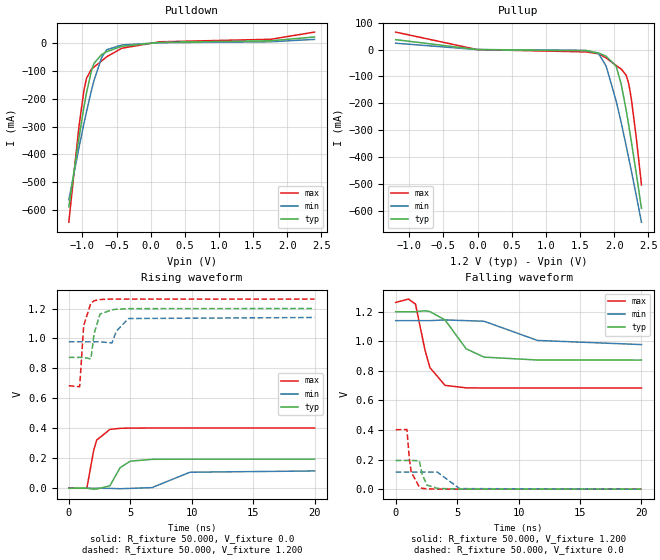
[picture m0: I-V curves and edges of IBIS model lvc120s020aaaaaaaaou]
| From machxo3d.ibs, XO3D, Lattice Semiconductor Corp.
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|   Model lvc120s020aaaaaaaaou
[Model] lvc120s020aaaaaaaaou
Model_type Output
Polarity   Non-Inverting
Enable   Active-High
Vmeas =  0.600V
Cref =  0.0F
Rref =  1.000M
Vref =  0.0V
C_comp   4.200pF   3.800pF   7.500pF
[Temperature Range]   25.000   0.105k   -40.000
[Voltage Range]   1.200V   1.140V   1.260V
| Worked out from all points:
|   slope of the pulldown table from 0 to 0.18 V, typ, clamps not added: 55.1 ohm
|   slope of the pullup table from 0 to 0.18 V, typ, clamps not added: 85.3 ohm
|   rising waveform, R_fixture 50.000, V_fixture 0.0: 20-80 % time 915ps typ, 1.63ns min, 579ps max; typ from 0 V to 0.194 V
|   rising waveform, R_fixture 50.000, V_fixture 1.200: 20-80 % time 365ps typ, 410ps min, 382ps max; typ from 0.873 V to 1.2 V
|   falling waveform, R_fixture 50.000, V_fixture 1.200: 20-80 % time 1.82ns typ, 3.11ns min, 986ps max; typ from 1.2 V to 0.873 V
|   falling waveform, R_fixture 50.000, V_fixture 0.0: 20-80 % time 395ps typ, 462ps min, 380ps max; typ from 0.194 V to 0 V
[Pulldown]
|Voltage   I(typ)   I(min)   I(max)
-1.2V     -588.5mA   -562.6mA   -643.2mA
-1.052V   -341.1mA   -376.3mA   -300.5mA
-978mV    -229mA     -288.4mA   -169.1mA
-941mV    -178.7mA   -246.5mA   -126.6mA
-867mV    -98.35mA   -168.4mA   -92.94mA
-830mV    -72.38mA   -133.3mA   -85.88mA
-719mV    -41.09mA   -51.67mA   -64.01mA
-645mV    -30.75mA   -23.95mA   -49.03mA
-423mV    -11.33mA   -6.73mA    -18.4mA
132mV     2.541mA    1.32mA     4.656mA
1.76V     8.299mA    4.874mA    13.72mA
2.4V      22.06mA    13.29mA    39.53mA
[Pullup]
|Voltage   I(typ)   I(min)   I(max)
-1.2V     36.91mA    23.72mA    65.09mA
-5mV      72.11uA    46.33uA    -26.46uA
1.586V    -4.313mA   -2.851mA   -8.695mA
1.771V    -12.45mA   -14.56mA   -15.38mA
1.882V    -24.63mA   -61.17mA   -31.07mA
2.03V     -62.24mA   -191.6mA   -59.45mA
2.104V    -129.6mA   -272.9mA   -72.75mA
2.178V    -228.3mA   -360.4mA   -95.8mA
2.215V    -284mA     -405.7mA   -129.1mA
2.252V    -342.3mA   -451.9mA   -183.9mA
2.326V    -464.4mA   -546.1mA   -332.1mA
2.4V      -591.1mA   -642.4mA   -503.2mA
[Ramp]
| variable   typ   min   max
dV/dt_r   0.117/0.892n   69.290m/1.667n   0.241/0.586n
dV/dt_f   0.196/1.789n   97.146m/3.072n   0.346/0.972n
R_load = 50.000
[Rising Waveform]
R_fixture= 50.000
V_fixture= 0.0
V_fixture_min= 0.0
V_fixture_max= 0.0
|time   V(typ)   V(min)   V(max)
0s        4.708nV    57.48nV    2.342nV
1.467ns   90.66uV    13.48uV    -233.5uV
2.026ns   -6.137mV   66.77uV    254.5mV
2.269ns   -5.478mV   195.4uV    321.7mV
3.345ns   16.61mV    -767.7uV   392.9mV
4.175ns   137.4mV    -3.391mV   400mV
5.005ns   180.8mV    -859.1uV   401.7mV
6.771ns   193mV      4.271mV    402.2mV
9.856ns   194.2mV    107mV      402.3mV
20ns      194.3mV    115.5mV    402.3mV
[Rising Waveform]
R_fixture= 50.000
V_fixture= 1.200
V_fixture_min= 1.140
V_fixture_max= 1.260
|time   V(typ)   V(min)   V(max)
0s        873.4mV    977.9mV    684.3mV
883ps     873.4mV    977.9mV    678.1mV
1.21ns    873.2mV    977.9mV    1.086V
1.795ns   863.4mV    977.8mV    1.236V
2.065ns   1.034V     977.7mV    1.252V
2.538ns   1.163V     977.9mV    1.26V
3.513ns   1.191V     969.9mV    1.263V
3.862ns   1.195V     1.048V     1.263V
4.85ns    1.199V     1.133V     1.263V
20ns      1.2V       1.14V      1.263V
[Falling Waveform]
R_fixture= 50.000
V_fixture= 1.200
V_fixture_min= 1.140
V_fixture_max= 1.260
|time   V(typ)   V(min)   V(max)
0s        1.2V       1.14V      1.263V
1.04ns    1.2V       1.14V      1.286V
1.612ns   1.2V       1.14V      1.252V
2.386ns   1.207V     1.14V      940mV
2.788ns   1.201V     1.14V      822mV
4.015ns   1.145V     1.145V     702.2mV
5.73ns    949.7mV    1.14V      685.3mV
7.192ns   893.2mV    1.136V     684.4mV
11.54ns   873.7mV    1.006V     684.3mV
20ns      873.4mV    978.1mV    684.3mV
[Falling Waveform]
R_fixture= 50.000
V_fixture= 0.0
V_fixture_min= 0.0
V_fixture_max= 0.0
|time   V(typ)   V(min)   V(max)
0s        194.3mV    115.5mV    402.3mV
915ps     194.3mV    115.5mV    403.6mV
1.109ns   194.3mV    115.5mV    206.4mV
1.266ns   194.3mV    115.5mV    115.9mV
1.926ns   192.4mV    115.5mV    13.96mV
2.129ns   107.7mV    115.5mV    6.357mV
2.531ns   28.28mV    115.4mV    2.13mV
3.397ns   5.221mV    115.1mV    386.9uV
5.192ns   606.5uV    3.815mV    15.25uV
20ns      12.54nV    909.9nV    3.115nV
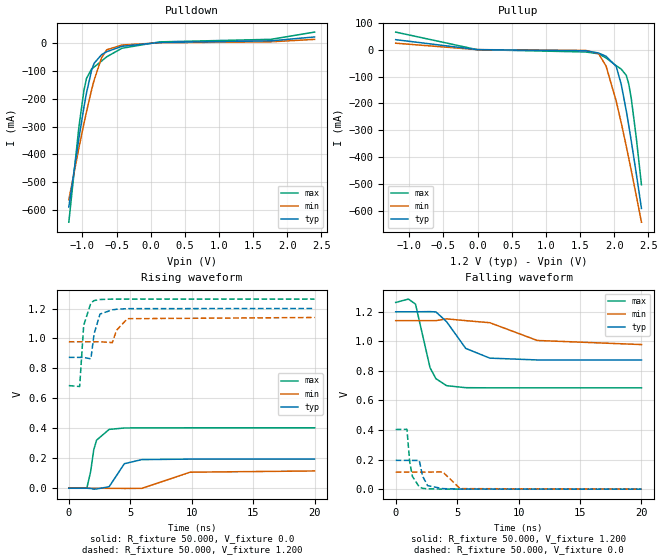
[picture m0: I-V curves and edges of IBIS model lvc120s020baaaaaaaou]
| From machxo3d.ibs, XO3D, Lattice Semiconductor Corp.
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|   Model lvc120s020baaaaaaaou
[Model] lvc120s020baaaaaaaou
Model_type Output
Polarity   Non-Inverting
Enable   Active-High
Vmeas =  0.600V
Cref =  0.0F
Rref =  1.000M
Vref =  0.0V
C_comp   4.200pF   3.800pF   7.500pF
[Temperature Range]   25.000   0.105k   -40.000
[Voltage Range]   1.200V   1.140V   1.260V
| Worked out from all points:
|   slope of the pulldown table from 0 to 0.18 V, typ, clamps not added: 55.1 ohm
|   slope of the pullup table from 0 to 0.18 V, typ, clamps not added: 85 ohm
|   rising waveform, R_fixture 50.000, V_fixture 0.0: 20-80 % time 909ps typ, 1.63ns min, 582ps max; typ from 0 V to 0.195 V
|   rising waveform, R_fixture 50.000, V_fixture 1.200: 20-80 % time 363ps typ, 416ps min, 382ps max; typ from 0.874 V to 1.2 V
|   falling waveform, R_fixture 50.000, V_fixture 1.200: 20-80 % time 1.83ns typ, 3.07ns min, 987ps max; typ from 1.2 V to 0.874 V
|   falling waveform, R_fixture 50.000, V_fixture 0.0: 20-80 % time 401ps typ, 464ps min, 384ps max; typ from 0.195 V to 0 V
[Pulldown]
|Voltage   I(typ)   I(min)   I(max)
-1.2V     -588.5mA   -562.6mA   -643.2mA
-1.052V   -341.1mA   -376.3mA   -300.5mA
-978mV    -229mA     -288.4mA   -169.1mA
-941mV    -178.7mA   -246.5mA   -126.7mA
-867mV    -98.35mA   -168.4mA   -92.95mA
-830mV    -72.39mA   -133.3mA   -85.89mA
-719mV    -41.1mA    -51.67mA   -64.03mA
-645mV    -30.75mA   -23.95mA   -49.04mA
-423mV    -11.34mA   -6.735mA   -18.42mA
132mV     2.529mA    1.315mA    4.626mA
1.76V     8.329mA    4.905mA    13.76mA
2.4V      22.31mA    13.61mA    39.77mA
[Pullup]
|Voltage   I(typ)   I(min)   I(max)
-1.2V     37.17mA    24.01mA    65.38mA
-5mV      72.32uA    46.44uA    -26.55uA
1.586V    -4.324mA   -2.856mA   -8.722mA
1.771V    -12.46mA   -14.55mA   -15.4mA
1.882V    -24.64mA   -61.18mA   -31.08mA
2.03V     -62.24mA   -191.6mA   -59.46mA
2.104V    -129.6mA   -272.9mA   -72.75mA
2.178V    -228.3mA   -360.4mA   -95.81mA
2.215V    -284mA     -405.7mA   -129.1mA
2.252V    -342.3mA   -451.9mA   -183.9mA
2.326V    -464.4mA   -546.1mA   -332.1mA
2.4V      -591.1mA   -642.4mA   -503.3mA
[Ramp]
| variable   typ   min   max
dV/dt_r   0.117/0.899n   69.347m/1.618n   0.242/0.586n
dV/dt_f   0.196/1.818n   97.061m/3.128n   0.345/0.973n
R_load = 50.000
[Rising Waveform]
R_fixture= 50.000
V_fixture= 0.0
V_fixture_min= 0.0
V_fixture_max= 0.0
|time   V(typ)   V(min)   V(max)
0s        284.9uV    165.7uV    490.2uV
1.466ns   361.8uV    179.9uV    957.1uV
1.778ns   -1.25mV    179.9uV    112.3mV
2.03ns    -5.893mV   271.8uV    257.3mV
2.261ns   -4.949mV   349.5uV    321.5mV
3.287ns   11.03mV    -248.8uV   393.2mV
4.52ns    164mV      -1.195mV   402.4mV
5.933ns   191.4mV    -860uV     403.5mV
9.87ns    194.8mV    107.4mV    403.7mV
20ns      194.9mV    115.7mV    403.7mV
[Rising Waveform]
R_fixture= 50.000
V_fixture= 1.200
V_fixture_min= 1.140
V_fixture_max= 1.260
|time   V(typ)   V(min)   V(max)
0s        873.8mV    978mV      685.5mV
883ps     873.9mV    978mV      679.3mV
1.21ns    873.7mV    978mV      1.087V
1.795ns   863.8mV    978mV      1.237V
2.062ns   1.033V     977.9mV    1.253V
2.54ns    1.163V     978mV      1.26V
3.541ns   1.191V     972.4mV    1.263V
3.883ns   1.195V     1.055V     1.263V
4.769ns   1.199V     1.132V     1.263V
20ns      1.2V       1.14V      1.263V
[Falling Waveform]
R_fixture= 50.000
V_fixture= 1.200
V_fixture_min= 1.140
V_fixture_max= 1.260
|time   V(typ)   V(min)   V(max)
0s        1.2V       1.14V      1.263V
1.039ns   1.2V       1.14V      1.286V
1.612ns   1.2V       1.14V      1.252V
2.796ns   1.201V     1.14V      821.4mV
3.276ns   1.199V     1.14V      747.3mV
4.142ns   1.133V     1.152V     700.2mV
5.698ns   952.3mV    1.14V      686.6mV
7.66ns    886.5mV    1.126V     685.6mV
11.52ns   874.2mV    1.006V     685.5mV
20ns      873.8mV    978.2mV    685.5mV
[Falling Waveform]
R_fixture= 50.000
V_fixture= 0.0
V_fixture_min= 0.0
V_fixture_max= 0.0
|time   V(typ)   V(min)   V(max)
0s        194.9mV    115.8mV    403.7mV
915ps     194.9mV    115.8mV    405.1mV
1.145ns   194.9mV    115.8mV    180.7mV
1.366ns   194.7mV    115.8mV    85.67mV
1.919ns   194.3mV    115.8mV    15.3mV
2.187ns   88.26mV    115.8mV    5.957mV
2.599ns   23.95mV    115.7mV    2.348mV
3.822ns   3.829mV    117mV      664.9uV
5.247ns   901.1uV    3.744mV    506.4uV
20ns      284.9uV    166.6uV    490.1uV
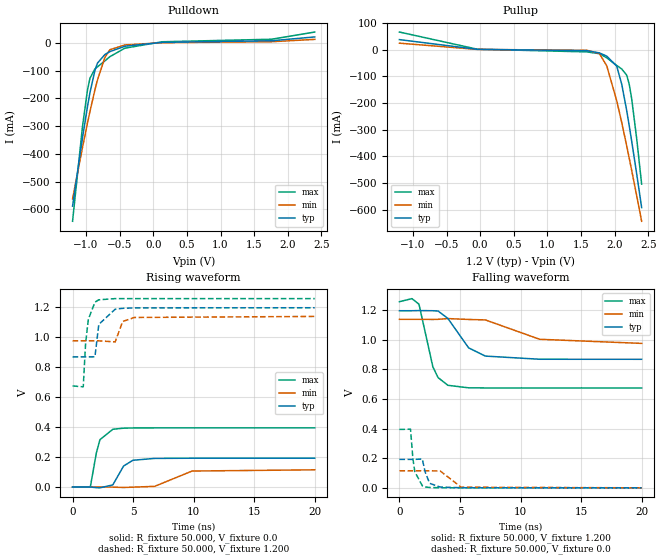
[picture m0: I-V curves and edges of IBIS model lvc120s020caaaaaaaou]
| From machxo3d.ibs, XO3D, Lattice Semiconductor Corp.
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|   Model lvc120s020caaaaaaaou
[Model] lvc120s020caaaaaaaou
Model_type Output
Polarity   Non-Inverting
Enable   Active-High
Vmeas =  0.600V
Cref =  0.0F
Rref =  1.000M
Vref =  0.0V
C_comp   4.200pF   3.800pF   7.500pF
[Temperature Range]   25.000   0.105k   -40.000
[Voltage Range]   1.200V   1.140V   1.260V
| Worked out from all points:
|   slope of the pulldown table from 0 to 0.18 V, typ, clamps not added: 54.5 ohm
|   slope of the pullup table from 0 to 0.18 V, typ, clamps not added: 85.2 ohm
|   rising waveform, R_fixture 50.000, V_fixture 0.0: 20-80 % time 902ps typ, 1.67ns min, 578ps max; typ from 0 V to 0.192 V
|   rising waveform, R_fixture 50.000, V_fixture 1.200: 20-80 % time 371ps typ, 422ps min, 400ps max; typ from 0.869 V to 1.2 V
|   falling waveform, R_fixture 50.000, V_fixture 1.200: 20-80 % time 1.86ns typ, 3.2ns min, 984ps max; typ from 1.2 V to 0.869 V
|   falling waveform, R_fixture 50.000, V_fixture 0.0: 20-80 % time 393ps typ, 460ps min, 367ps max; typ from 0.192 V to 0 V
[Pulldown]
|Voltage   I(typ)   I(min)   I(max)
-1.2V     -588.5mA   -562.6mA   -643.3mA
-1.052V   -341.1mA   -376.3mA   -300.6mA
-978mV    -229mA     -288.4mA   -169.2mA
-941mV    -178.7mA   -246.5mA   -126.7mA
-867mV    -98.4mA    -168.4mA   -93mA
-830mV    -72.44mA   -133.3mA   -85.94mA
-719mV    -41.14mA   -51.7mA    -64.09mA
-645mV    -30.8mA    -23.97mA   -49.11mA
-423mV    -11.42mA   -6.781mA   -18.53mA
132mV     2.569mA    1.333mA    4.719mA
1.76V     8.38mA     4.913mA    13.89mA
2.4V      22.23mA    13.36mA    39.82mA
[Pullup]
|Voltage   I(typ)   I(min)   I(max)
-1.2V     37.08mA    23.8mA     65.42mA
-42mV     727.4uA    444uA      1.217mA
1.586V    -4.396mA   -2.904mA   -8.825mA
1.771V    -12.51mA   -14.58mA   -15.48mA
1.882V    -24.68mA   -61.2mA    -31.14mA
2.03V     -62.29mA   -191.6mA   -59.5mA
2.104V    -129.7mA   -273mA     -72.8mA
2.178V    -228.4mA   -360.4mA   -95.85mA
2.215V    -284.1mA   -405.7mA   -129.1mA
2.252V    -342.4mA   -451.9mA   -184mA
2.326V    -464.4mA   -546.1mA   -332.2mA
2.4V      -591.1mA   -642.4mA   -503.3mA
[Ramp]
| variable   typ   min   max
dV/dt_r   0.115/0.879n   68.968m/1.640n   0.237/0.580n
dV/dt_f   0.197/1.803n   97.455m/3.109n   0.348/0.980n
R_load = 50.000
[Rising Waveform]
R_fixture= 50.000
V_fixture= 0.0
V_fixture_min= 0.0
V_fixture_max= 0.0
|time   V(typ)   V(min)   V(max)
0s        4.535nV    56.85nV    2.146nV
1.466ns   88.27uV    13.4uV     -234.9uV
1.965ns   -4.425mV   66.66uV    227.9mV
2.262ns   -5.422mV   194.6uV    316.2mV
3.324ns   14.24mV    -741.1uV   385.6mV
4.214ns   140.2mV    -3.063mV   392.9mV
4.983ns   178.7mV    -851.9uV   394.3mV
6.775ns   191.1mV    4.356mV    394.8mV
9.871ns   192.3mV    106.7mV    394.8mV
20ns      192.4mV    114.9mV    394.9mV
[Rising Waveform]
R_fixture= 50.000
V_fixture= 1.200
V_fixture_min= 1.140
V_fixture_max= 1.260
|time   V(typ)   V(min)   V(max)
0s        868.8mV    976.1mV    675.1mV
883ps     868.9mV    976.1mV    668.8mV
1.076ns   868.8mV    976.1mV    958.3mV
1.301ns   868.8mV    976.1mV    1.119V
1.848ns   869.4mV    976.1mV    1.234V
2.167ns   1.086V     976mV      1.25V
3.521ns   1.187V     968.8mV    1.258V
4.135ns   1.193V     1.105V     1.258V
5.097ns   1.196V     1.132V     1.258V
20ns      1.197V     1.139V     1.258V
[Falling Waveform]
R_fixture= 50.000
V_fixture= 1.200
V_fixture_min= 1.140
V_fixture_max= 1.260
|time   V(typ)   V(min)   V(max)
0s        1.197V     1.139V     1.258V
1.032ns   1.197V     1.139V     1.279V
1.615ns   1.198V     1.139V     1.241V
2.761ns   1.197V     1.138V     817.6mV
3.194ns   1.195V     1.139V     744.9mV
4ns       1.145V     1.144V     693mV
5.715ns   946mV      1.138V     676mV
7.093ns   890.5mV    1.135V     675.2mV
11.58ns   869.1mV    1.004V     675.1mV
20ns      868.8mV    976.3mV    675.1mV
[Falling Waveform]
R_fixture= 50.000
V_fixture= 0.0
V_fixture_min= 0.0
V_fixture_max= 0.0
|time   V(typ)   V(min)   V(max)
0s        192.4mV    114.9mV    394.9mV
915ps     192.4mV    115mV      396.2mV
1.112ns   192.4mV    115mV      196.9mV
1.27ns    192.3mV    115mV      108.6mV
1.887ns   194.7mV    115mV      14.26mV
2.129ns   105.9mV    115mV      6.001mV
2.494ns   30.47mV    114.9mV    2.203mV
3.359ns   5.328mV    114.5mV    423.4uV
5.102ns   655.9uV    4.398mV    21.13uV
20ns      7.866nV    899.2nV    -3.439nV
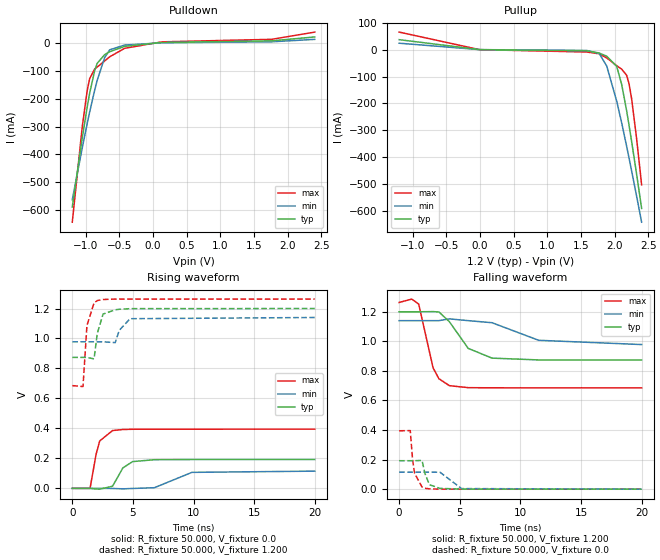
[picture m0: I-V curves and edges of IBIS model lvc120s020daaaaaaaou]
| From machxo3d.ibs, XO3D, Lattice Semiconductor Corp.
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|   Model lvc120s020daaaaaaaou
[Model] lvc120s020daaaaaaaou
Model_type Output
Polarity   Non-Inverting
Enable   Active-High
Vmeas =  0.600V
Cref =  0.0F
Rref =  1.000M
Vref =  0.0V
C_comp   4.200pF   3.800pF   7.500pF
[Temperature Range]   25.000   0.105k   -40.000
[Voltage Range]   1.200V   1.140V   1.260V
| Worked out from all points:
|   slope of the pulldown table from 0 to 0.18 V, typ, clamps not added: 54.5 ohm
|   slope of the pullup table from 0 to 0.18 V, typ, clamps not added: 85 ohm
|   rising waveform, R_fixture 50.000, V_fixture 0.0: 20-80 % time 906ps typ, 1.66ns min, 578ps max; typ from 0 V to 0.192 V
|   rising waveform, R_fixture 50.000, V_fixture 1.200: 20-80 % time 363ps typ, 416ps min, 382ps max; typ from 0.874 V to 1.2 V
|   falling waveform, R_fixture 50.000, V_fixture 1.200: 20-80 % time 1.83ns typ, 3.15ns min, 987ps max; typ from 1.2 V to 0.874 V
|   falling waveform, R_fixture 50.000, V_fixture 0.0: 20-80 % time 393ps typ, 466ps min, 367ps max; typ from 0.192 V to 0 V
[Pulldown]
|Voltage   I(typ)   I(min)   I(max)
-1.2V     -588.5mA   -562.6mA   -643.3mA
-1.052V   -341.1mA   -376.3mA   -300.6mA
-978mV    -229mA     -288.4mA   -169.2mA
-941mV    -178.7mA   -246.5mA   -126.7mA
-867mV    -98.4mA    -168.4mA   -93mA
-830mV    -72.44mA   -133.3mA   -85.94mA
-719mV    -41.14mA   -51.7mA    -64.09mA
-645mV    -30.8mA    -23.97mA   -49.11mA
-423mV    -11.42mA   -6.781mA   -18.53mA
132mV     2.569mA    1.333mA    4.719mA
1.76V     8.329mA    4.905mA    13.76mA
2.4V      22.31mA    13.61mA    39.77mA
[Pullup]
|Voltage   I(typ)   I(min)   I(max)
-1.2V     37.17mA    24.01mA    65.38mA
-5mV      72.32uA    46.44uA    -26.55uA
1.586V    -4.396mA   -2.904mA   -8.825mA
1.771V    -12.51mA   -14.58mA   -15.48mA
1.882V    -24.68mA   -61.2mA    -31.14mA
2.03V     -62.29mA   -191.6mA   -59.5mA
2.104V    -129.7mA   -273mA     -72.8mA
2.178V    -228.4mA   -360.4mA   -95.85mA
2.215V    -284.1mA   -405.7mA   -129.1mA
2.252V    -342.4mA   -451.9mA   -184mA
2.326V    -464.4mA   -546.1mA   -332.2mA
2.4V      -591.1mA   -642.4mA   -503.3mA
[Ramp]
| variable   typ   min   max
dV/dt_r   0.115/0.879n   68.968m/1.640n   0.237/0.580n
dV/dt_f   0.196/1.819n   97.061m/3.128n   0.345/0.973n
R_load = 50.000
[Rising Waveform]
R_fixture= 50.000
V_fixture= 0.0
V_fixture_min= 0.0
V_fixture_max= 0.0
|time   V(typ)   V(min)   V(max)
0s        4.535nV    56.85nV    2.146nV
1.466ns   88.31uV    13.38uV    -234.9uV
1.965ns   -4.388mV   66.66uV    227.9mV
2.262ns   -5.422mV   194.6uV    316.2mV
3.324ns   14.24mV    -739.6uV   385.6mV
4.175ns   136.5mV    -3.382mV   392.6mV
4.978ns   178.6mV    -851.9uV   394.3mV
6.775ns   191.1mV    4.356mV    394.8mV
9.871ns   192.3mV    106.7mV    394.8mV
20ns      192.4mV    114.9mV    394.9mV
[Rising Waveform]
R_fixture= 50.000
V_fixture= 1.200
V_fixture_min= 1.140
V_fixture_max= 1.260
|time   V(typ)   V(min)   V(max)
0s        873.8mV    978mV      685.5mV
883ps     873.9mV    978mV      679.3mV
1.21ns    873.7mV    978mV      1.087V
1.795ns   863.8mV    978mV      1.237V
2.062ns   1.033V     977.9mV    1.253V
2.54ns    1.163V     977.9mV    1.26V
3.541ns   1.191V     972.4mV    1.263V
3.883ns   1.195V     1.055V     1.263V
4.769ns   1.199V     1.132V     1.263V
20ns      1.2V       1.14V      1.263V
[Falling Waveform]
R_fixture= 50.000
V_fixture= 1.200
V_fixture_min= 1.140
V_fixture_max= 1.260
|time   V(typ)   V(min)   V(max)
0s        1.2V       1.14V      1.263V
1.039ns   1.2V       1.14V      1.286V
1.612ns   1.2V       1.14V      1.252V
2.796ns   1.201V     1.14V      821.4mV
3.276ns   1.199V     1.14V      747.3mV
4.142ns   1.133V     1.152V     700.2mV
5.698ns   952.3mV    1.14V      686.6mV
7.66ns    886.5mV    1.126V     685.6mV
11.51ns   874.2mV    1.007V     685.5mV
20ns      873.8mV    978.2mV    685.5mV
[Falling Waveform]
R_fixture= 50.000
V_fixture= 0.0
V_fixture_min= 0.0
V_fixture_max= 0.0
|time   V(typ)   V(min)   V(max)
0s        192.4mV    114.9mV    394.9mV
915ps     192.4mV    115mV      396.2mV
1.112ns   192.4mV    115mV      196.9mV
1.27ns    192.3mV    115mV      108.6mV
1.887ns   194.7mV    115mV      14.26mV
2.129ns   105.9mV    115mV      6.001mV
2.495ns   30.38mV    114.9mV    2.203mV
3.369ns   5.207mV    114.5mV    423.4uV
5.148ns   608uV      4.037mV    21.13uV
20ns      7.866nV    899.4nV    -3.439nV
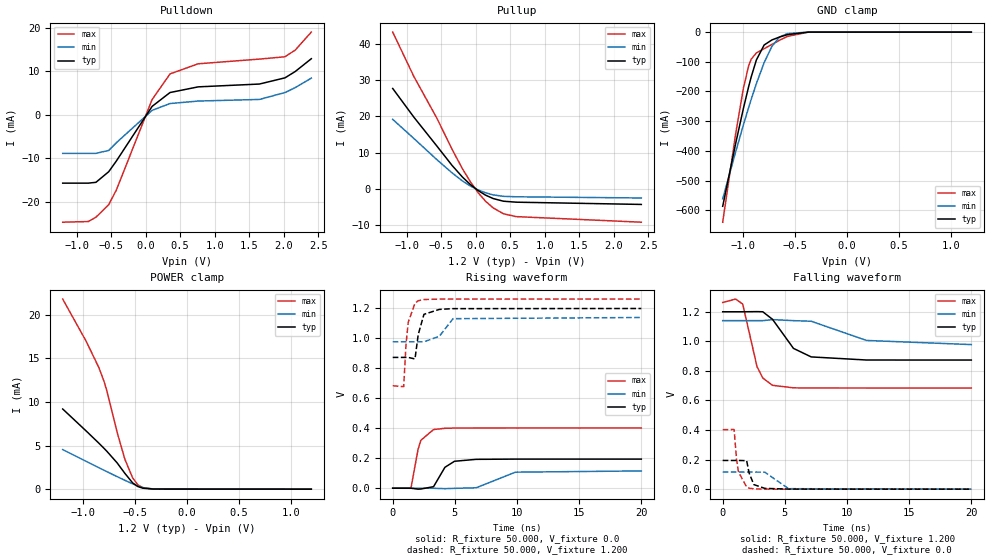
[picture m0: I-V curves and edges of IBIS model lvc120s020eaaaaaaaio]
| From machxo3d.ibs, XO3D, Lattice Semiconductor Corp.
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|   Model lvc120s020eaaaaaaaio
[Model] lvc120s020eaaaaaaaio
Model_type I/O
Polarity   Non-Inverting
Enable   Active-Low
Vinl =  0.420V
Vinh =  0.780V
Vmeas =  0.600V
Cref =  0.0F
Rref =  1.000M
Vref =  0.0V
C_comp   4.200pF   3.800pF   7.500pF
[Temperature Range]   25.000   0.105k   -40.000
[Voltage Range]   1.200V   1.140V   1.260V
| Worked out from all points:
|   slope of the pulldown table from 0 to 0.18 V, typ, clamps not added: 55.1 ohm
|   slope of the pullup table from 0 to 0.18 V, typ, clamps not added: 85.3 ohm
|   GND clamp passes 1 mA (typ) near -0.44 V on its own axis
|   POWER clamp passes 1 mA (typ) near -0.55 V on its own axis
|   rising waveform, R_fixture 50.000, V_fixture 0.0: 20-80 % time 914ps typ, 1.64ns min, 587ps max; typ from 0 V to 0.194 V
|   rising waveform, R_fixture 50.000, V_fixture 1.200: 20-80 % time 367ps typ, 416ps min, 385ps max; typ from 0.873 V to 1.2 V
|   falling waveform, R_fixture 50.000, V_fixture 1.200: 20-80 % time 1.85ns typ, 3.11ns min, 980ps max; typ from 1.2 V to 0.873 V
|   falling waveform, R_fixture 50.000, V_fixture 0.0: 20-80 % time 407ps typ, 468ps min, 385ps max; typ from 0.194 V to 0 V
[Pulldown]
|Voltage   I(typ)   I(min)   I(max)
-1.2V     -15.77mA   -8.921mA   -24.76mA
-830mV    -15.77mA   -8.921mA   -24.61mA
-719mV    -15.58mA   -8.921mA   -23.61mA
-534mV    -13.14mA   -8.234mA   -20.74mA
-423mV    -10.67mA   -6.463mA   -17.35mA
95mV      1.91mA     997.3uA    3.496mA
354mV     5.095mA    2.558mA    9.38mA
761mV     6.397mA    3.131mA    11.71mA
1.649V    7.049mA    3.505mA    12.79mA
2.019V    8.479mA    5.088mA    13.33mA
2.167V    9.932mA    6.226mA    14.87mA
2.4V      12.88mA    8.416mA    19.01mA
[Pullup]
|Voltage   I(typ)   I(min)   I(max)
-1.2V     27.73mA    19.19mA    43.32mA
-893mV    19.78mA    13.89mA    31.01mA
-560mV    11.8mA     8.039mA    19.5mA
-338mV    6.396mA    4.353mA    10.82mA
-190mV    3.229mA    2.154mA    5.518mA
-79mV     1.223mA    799.3uA    2.039mA
32mV      -444uA     -284.1uA   -972.5uA
143mV     -1.752mA   -1.109mA   -3.419mA
254mV     -2.703mA   -1.688mA   -5.288mA
402mV     -3.439mA   -2.096mA   -6.902mA
587mV     -3.713mA   -2.22mA    -7.705mA
2.4V      -4.336mA   -2.551mA   -9.246mA
[GND_clamp]
|Voltage   I(typ)   I(min)   I(max)
-1.2V     -586.8mA   -561.6mA   -640.3mA
-1.075V   -375.3mA   -403.2mA   -342.9mA
-1V       -256.8mA   -312.3mA   -188.8mA
-950mV    -184.3mA   -254.5mA   -114.1mA
-925mV    -151.1mA   -226.6mA   -91.26mA
-875mV    -93.95mA   -173.6mA   -69.99mA
-800mV    -43.5mA    -102.9mA   -56.04mA
-725mV    -26.4mA    -48.03mA   -41.57mA
-650mV    -16.5mA    -16.35mA   -27.16mA
-575mV    -8.667mA   -5.012mA   -14.69mA
-375mV    -183.5uA   -82.46uA   -270.8uA
1.2V      0A         0A         0A
[POWER_clamp]
|Voltage   I(typ)   I(min)   I(max)
-1.2V     9.182mA    4.531mA    21.77mA
-975mV    6.68mA     3.195mA    16.97mA
-850mV    5.256mA    2.452mA    13.9mA
-800mV    4.662mA    2.159mA    12.31mA
-775mV    4.355mA    2.014mA    11.32mA
-675mV    3.015mA    1.438mA    6.52mA
-600mV    1.813mA    1.015mA    3.43mA
-525mV    717.6uA    612.9uA    1.296mA
-475mV    302.2uA    372.2uA    507.9uA
-425mV    111uA      180.2uA    159.4uA
-325mV    13.15uA    20.51uA    12.23uA
1.2V      0A         0A         3.808nA
[Ramp]
| variable   typ   min   max
dV/dt_r   0.117/0.888n   69.290m/1.663n   0.241/0.593n
dV/dt_f   0.196/1.802n   97.146m/3.072n   0.346/0.976n
R_load = 50.000
[Rising Waveform]
R_fixture= 50.000
V_fixture= 0.0
V_fixture_min= 0.0
V_fixture_max= 0.0
|time   V(typ)   V(min)   V(max)
0s        4.736nV    57.27nV    2.383nV
1.466ns   64.37uV    14.49uV    -364.5uV
2.035ns   -6.349mV   66.89uV    257.2mV
2.265ns   -5.429mV   193.7uV    320.3mV
3.286ns   10.34mV    -414.4uV   391.7mV
4.201ns   139.7mV    -3.047mV   400.1mV
4.97ns    179.9mV    -864.2uV   401.6mV
6.711ns   192.8mV    2.987mV    402.2mV
9.877ns   194.3mV    107.2mV    402.3mV
20ns      194.3mV    115.5mV    402.3mV
[Rising Waveform]
R_fixture= 50.000
V_fixture= 1.200
V_fixture_min= 1.140
V_fixture_max= 1.260
|time   V(typ)   V(min)   V(max)
0s        873.4mV    977.9mV    684.3mV
883ps     873.4mV    977.9mV    678.1mV
1.076ns   873.3mV    977.9mV    968.5mV
1.251ns   873.3mV    977.9mV    1.108V
1.792ns   863.1mV    977.8mV    1.236V
2.053ns   1.026V     977.7mV    1.252V
2.512ns   1.161V     977.8mV    1.26V
3.75ns    1.194V     1.014V     1.263V
4.852ns   1.199V     1.132V     1.263V
20ns      1.2V       1.14V      1.263V
[Falling Waveform]
R_fixture= 50.000
V_fixture= 1.200
V_fixture_min= 1.140
V_fixture_max= 1.260
|time   V(typ)   V(min)   V(max)
0s        1.2V       1.14V      1.263V
1.04ns    1.2V       1.14V      1.286V
1.61ns    1.2V       1.14V      1.252V
2.762ns   1.201V     1.14V      828.1mV
3.226ns   1.2V       1.14V      751.7mV
4.006ns   1.149V     1.147V     702.6mV
5.693ns   952.3mV    1.14V      685.4mV
7.117ns   894.7mV    1.136V     684.5mV
11.57ns   873.7mV    1.006V     684.3mV
20ns      873.4mV    978.1mV    684.3mV
[Falling Waveform]
R_fixture= 50.000
V_fixture= 0.0
V_fixture_min= 0.0
V_fixture_max= 0.0
|time   V(typ)   V(min)   V(max)
0s        194.3mV    115.5mV    402.3mV
915ps     194.3mV    115.5mV    403.6mV
1.109ns   194.3mV    115.5mV    206.7mV
1.262ns   194.3mV    115.5mV    118.3mV
1.925ns   192.8mV    115.5mV    14.21mV
2.123ns   110mV      115.5mV    6.59mV
2.504ns   31.01mV    115.5mV    2.257mV
3.378ns   5.437mV    115.1mV    386.5uV
5.298ns   533.6uV    3.331mV    15.01uV
20ns      12.65nV    911.7nV    3.151nV
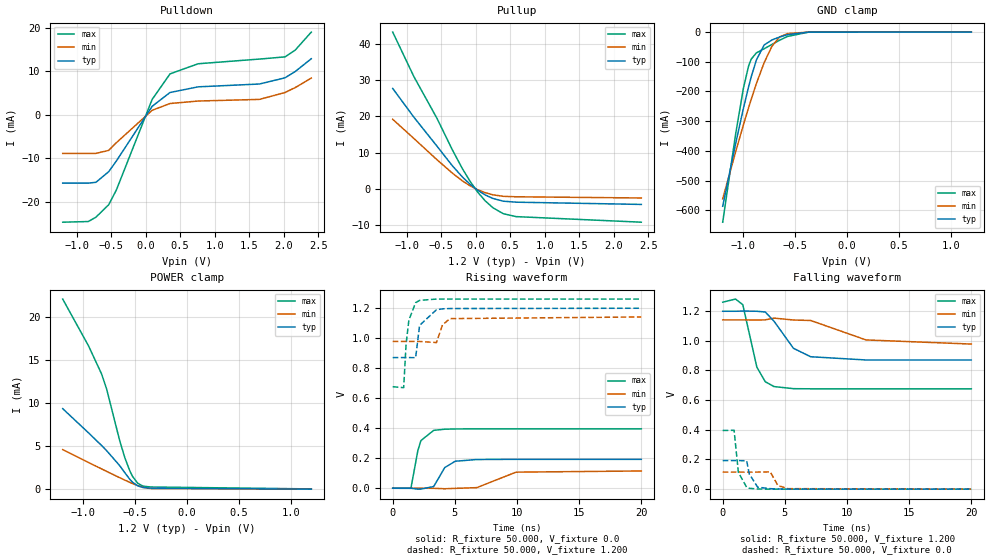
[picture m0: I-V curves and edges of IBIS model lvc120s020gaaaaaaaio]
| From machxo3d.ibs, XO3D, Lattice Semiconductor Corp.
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|   Model lvc120s020gaaaaaaaio
[Model] lvc120s020gaaaaaaaio
Model_type I/O
Polarity   Non-Inverting
Enable   Active-Low
Vinl =  0.420V
Vinh =  0.780V
Vmeas =  0.600V
Cref =  0.0F
Rref =  1.000M
Vref =  0.0V
C_comp   4.200pF   3.800pF   7.500pF
[Temperature Range]   25.000   0.105k   -40.000
[Voltage Range]   1.200V   1.140V   1.260V
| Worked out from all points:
|   slope of the pulldown table from 0 to 0.18 V, typ, clamps not added: 55.1 ohm
|   slope of the pullup table from 0 to 0.18 V, typ, clamps not added: 85.3 ohm
|   GND clamp passes 1 mA (typ) near -0.44 V on its own axis
|   POWER clamp passes 1 mA (typ) near -0.54 V on its own axis
|   rising waveform, R_fixture 50.000, V_fixture 0.0: 20-80 % time 923ps typ, 1.64ns min, 578ps max; typ from 0 V to 0.192 V
|   rising waveform, R_fixture 50.000, V_fixture 1.200: 20-80 % time 373ps typ, 417ps min, 401ps max; typ from 0.869 V to 1.2 V
|   falling waveform, R_fixture 50.000, V_fixture 1.200: 20-80 % time 1.83ns typ, 3.08ns min, 984ps max; typ from 1.2 V to 0.869 V
|   falling waveform, R_fixture 50.000, V_fixture 0.0: 20-80 % time 397ps typ, 468ps min, 370ps max; typ from 0.192 V to 0 V
[Pulldown]
|Voltage   I(typ)   I(min)   I(max)
-1.2V     -15.77mA   -8.921mA   -24.76mA
-830mV    -15.77mA   -8.921mA   -24.61mA
-719mV    -15.58mA   -8.921mA   -23.61mA
-534mV    -13.14mA   -8.234mA   -20.74mA
-423mV    -10.67mA   -6.463mA   -17.35mA
95mV      1.91mA     997.3uA    3.496mA
354mV     5.095mA    2.558mA    9.38mA
761mV     6.397mA    3.131mA    11.71mA
1.649V    7.048mA    3.505mA    12.79mA
2.019V    8.474mA    5.088mA    13.29mA
2.167V    9.928mA    6.227mA    14.86mA
2.4V      12.87mA    8.417mA    19mA
[Pullup]
|Voltage   I(typ)   I(min)   I(max)
-1.2V     27.73mA    19.2mA     43.31mA
-893mV    19.77mA    13.89mA    30.99mA
-560mV    11.8mA     8.039mA    19.5mA
-338mV    6.396mA    4.353mA    10.82mA
-190mV    3.229mA    2.154mA    5.518mA
-79mV     1.223mA    799.3uA    2.039mA
32mV      -444uA     -284.1uA   -972.5uA
143mV     -1.752mA   -1.109mA   -3.419mA
254mV     -2.703mA   -1.688mA   -5.288mA
402mV     -3.439mA   -2.096mA   -6.902mA
587mV     -3.713mA   -2.22mA    -7.705mA
2.4V      -4.336mA   -2.551mA   -9.245mA
[GND_clamp]
|Voltage   I(typ)   I(min)   I(max)
-1.2V     -586.8mA   -561.7mA   -640.4mA
-1.075V   -375.3mA   -403.2mA   -342.9mA
-1V       -256.8mA   -312.4mA   -188.9mA
-950mV    -184.3mA   -254.5mA   -114.1mA
-925mV    -151.1mA   -226.6mA   -91.32mA
-875mV    -94.01mA   -173.6mA   -70.06mA
-800mV    -43.56mA   -102.9mA   -56.11mA
-725mV    -26.45mA   -48.06mA   -41.65mA
-650mV    -16.55mA   -16.39mA   -27.24mA
-575mV    -8.728mA   -5.059mA   -14.79mA
-375mV    -266.5uA   -129.3uA   -404.6uA
1.2V      0A         0A         0A
[POWER_clamp]
|Voltage   I(typ)   I(min)   I(max)
-1.2V     9.358mA    4.601mA    22.1mA
-950mV    6.537mA    3.101mA    16.64mA
-825mV    5.08mA     2.355mA    13.4mA
-775mV    4.466mA    2.06mA     11.6mA
-650mV    2.734mA    1.335mA    5.647mA
-600mV    1.907mA    1.053mA    3.642mA
-550mV    1.113mA    778.7uA    2.069mA
-525mV    798uA      647.5uA    1.472mA
-475mV    381.7uA    406uA      682.4uA
-425mV    196.4uA    214.2uA    354.3uA
-350mV    117.6uA    72.69uA    251.1uA
1.2V      0A         0A         29.9uA
[Ramp]
| variable   typ   min   max
dV/dt_r   0.115/0.899n   68.968m/1.631n   0.237/0.584n
dV/dt_f   0.197/1.798n   97.454m/3.147n   0.348/0.984n
R_load = 50.000
[Rising Waveform]
R_fixture= 50.000
V_fixture= 0.0
V_fixture_min= 0.0
V_fixture_max= 0.0
|time   V(typ)   V(min)   V(max)
0s        4.561nV    56.64nV    2.182nV
1.465ns   52.45uV    14.41uV    -365.4uV
2.021ns   -6.09mV    66.78uV    249.7mV
2.268ns   -5.481mV   192.6uV    316.9mV
3.298ns   11.52mV    -407.9uV   385.1mV
4.186ns   137.4mV    -3.35mV    392.6mV
5.029ns   179.6mV    -857.5uV   394.3mV
6.765ns   191.1mV    4.113mV    394.8mV
9.921ns   192.3mV    107.1mV    394.8mV
20ns      192.4mV    114.9mV    394.9mV
[Rising Waveform]
R_fixture= 50.000
V_fixture= 1.200
V_fixture_min= 1.140
V_fixture_max= 1.260
|time   V(typ)   V(min)   V(max)
0s        868.8mV    976.1mV    675.1mV
883ps     868.8mV    976.1mV    668.8mV
1.076ns   868.8mV    976.1mV    958.1mV
1.303ns   868.8mV    976.1mV    1.119V
1.845ns   868.4mV    976.1mV    1.234V
2.162ns   1.083V     976mV      1.249V
3.52ns    1.187V     968.7mV    1.258V
4.004ns   1.193V     1.086V     1.258V
4.604ns   1.195V     1.128V     1.258V
20ns      1.197V     1.139V     1.258V
[Falling Waveform]
R_fixture= 50.000
V_fixture= 1.200
V_fixture_min= 1.140
V_fixture_max= 1.260
|time   V(typ)   V(min)   V(max)
0s        1.197V     1.139V     1.258V
1.032ns   1.197V     1.139V     1.279V
1.616ns   1.198V     1.139V     1.241V
2.748ns   1.197V     1.138V     820.9mV
3.423ns   1.192V     1.139V     722.8mV
4.127ns   1.13V      1.151V     690.3mV
5.692ns   947.7mV    1.138V     676.1mV
7.073ns   891mV      1.135V     675.2mV
11.53ns   869.2mV    1.004V     675.1mV
20ns      868.8mV    976.3mV    675mV
[Falling Waveform]
R_fixture= 50.000
V_fixture= 0.0
V_fixture_min= 0.0
V_fixture_max= 0.0
|time   V(typ)   V(min)   V(max)
0s        192.4mV    114.9mV    394.9mV
915ps     192.4mV    115mV      396.2mV
1.261ns   192.4mV    115mV      112.7mV
1.925ns   190.8mV    115mV      13mV
2.14ns    101.8mV    115mV      5.786mV
2.812ns   13.49mV    115mV      1.051mV
3.822ns   3.242mV    116.2mV    155.3uV
4.444ns   1.346mV    24.26mV    85.85uV
5.245ns   564.3uV    3.536mV    38.63uV
20ns      6.485nV    905.9nV    -6.471nV
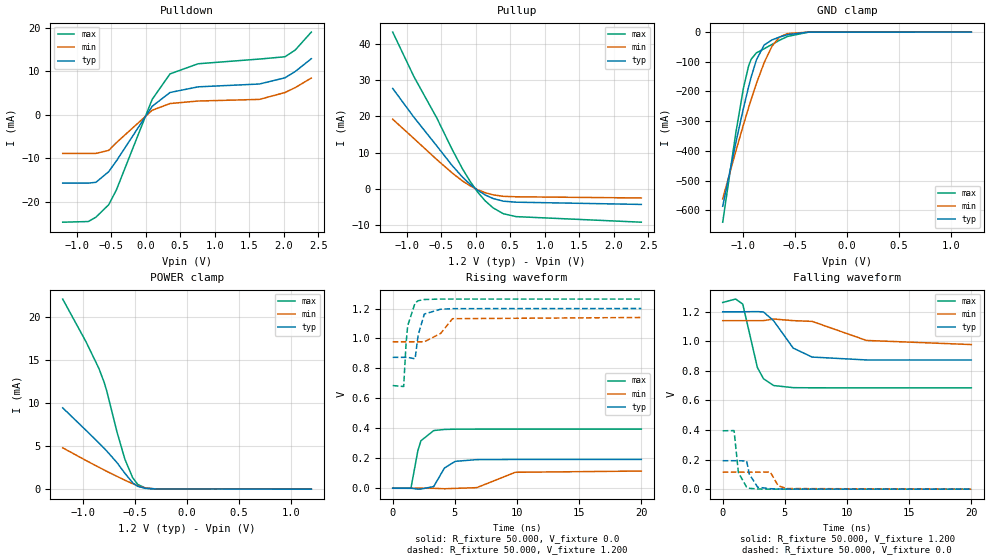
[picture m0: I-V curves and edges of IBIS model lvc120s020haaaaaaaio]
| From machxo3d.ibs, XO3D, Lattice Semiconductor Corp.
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|   Model lvc120s020haaaaaaaio
[Model] lvc120s020haaaaaaaio
Model_type I/O
Polarity   Non-Inverting
Enable   Active-Low
Vinl =  0.420V
Vinh =  0.780V
Vmeas =  0.600V
Cref =  0.0F
Rref =  1.000M
Vref =  0.0V
C_comp   4.200pF   3.800pF   7.500pF
[Temperature Range]   25.000   0.105k   -40.000
[Voltage Range]   1.200V   1.140V   1.260V
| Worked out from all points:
|   slope of the pulldown table from 0 to 0.18 V, typ, clamps not added: 55.1 ohm
|   slope of the pullup table from 0 to 0.18 V, typ, clamps not added: 85.3 ohm
|   GND clamp passes 1 mA (typ) near -0.44 V on its own axis
|   POWER clamp passes 1 mA (typ) near -0.55 V on its own axis
|   rising waveform, R_fixture 50.000, V_fixture 0.0: 20-80 % time 926ps typ, 1.64ns min, 578ps max; typ from 0 V to 0.192 V
|   rising waveform, R_fixture 50.000, V_fixture 1.200: 20-80 % time 368ps typ, 411ps min, 384ps max; typ from 0.874 V to 1.2 V
|   falling waveform, R_fixture 50.000, V_fixture 1.200: 20-80 % time 1.84ns typ, 3.14ns min, 991ps max; typ from 1.2 V to 0.874 V
|   falling waveform, R_fixture 50.000, V_fixture 0.0: 20-80 % time 397ps typ, 460ps min, 370ps max; typ from 0.192 V to 0 V
[Pulldown]
|Voltage   I(typ)   I(min)   I(max)
-1.2V     -15.77mA   -8.921mA   -24.76mA
-830mV    -15.77mA   -8.921mA   -24.61mA
-719mV    -15.58mA   -8.921mA   -23.61mA
-534mV    -13.14mA   -8.234mA   -20.74mA
-423mV    -10.67mA   -6.463mA   -17.35mA
95mV      1.91mA     997.3uA    3.496mA
354mV     5.095mA    2.558mA    9.38mA
761mV     6.397mA    3.131mA    11.71mA
1.649V    7.049mA    3.505mA    12.79mA
2.019V    8.476mA    5.088mA    13.32mA
2.167V    9.927mA    6.228mA    14.87mA
2.4V      12.87mA    8.42mA     19mA
[Pullup]
|Voltage   I(typ)   I(min)   I(max)
-1.2V     27.73mA    19.21mA    43.31mA
-893mV    19.77mA    13.89mA    31mA
-560mV    11.8mA     8.039mA    19.5mA
-338mV    6.396mA    4.353mA    10.82mA
-190mV    3.229mA    2.154mA    5.518mA
-79mV     1.223mA    799.3uA    2.039mA
32mV      -444uA     -284.1uA   -972.5uA
143mV     -1.752mA   -1.109mA   -3.419mA
254mV     -2.703mA   -1.688mA   -5.288mA
402mV     -3.439mA   -2.096mA   -6.902mA
587mV     -3.713mA   -2.22mA    -7.705mA
2.4V      -4.336mA   -2.551mA   -9.245mA
[GND_clamp]
|Voltage   I(typ)   I(min)   I(max)
-1.2V     -586.8mA   -561.7mA   -640.4mA
-1.075V   -375.3mA   -403.2mA   -342.9mA
-1V       -256.8mA   -312.4mA   -188.9mA
-950mV    -184.3mA   -254.5mA   -114.1mA
-925mV    -151.1mA   -226.6mA   -91.32mA
-875mV    -94.01mA   -173.6mA   -70.06mA
-800mV    -43.56mA   -102.9mA   -56.11mA
-725mV    -26.45mA   -48.06mA   -41.65mA
-650mV    -16.55mA   -16.39mA   -27.24mA
-575mV    -8.728mA   -5.059mA   -14.79mA
-375mV    -266.5uA   -129.3uA   -404.6uA
1.2V      -42.59nA   0A         -5.33uA
[POWER_clamp]
|Voltage   I(typ)   I(min)   I(max)
-1.2V     9.441mA    4.803mA    22.07mA
-975mV    6.83mA     3.329mA    17.11mA
-850mV    5.356mA    2.536mA    14mA
-800mV    4.744mA    2.228mA    12.4mA
-775mV    4.43mA     2.076mA    11.41mA
-675mV    3.065mA    1.478mA    6.596mA
-600mV    1.851mA    1.044mA    3.486mA
-525mV    744.7uA    632.6uA    1.337mA
-475mV    325.6uA    388.1uA    543.5uA
-400mV    86.39uA    124.7uA    120.1uA
-300mV    23.03uA    20.03uA    34.62uA
1.2V      0A         0A         0A
[Ramp]
| variable   typ   min   max
dV/dt_r   0.115/0.899n   68.968m/1.631n   0.237/0.584n
dV/dt_f   0.196/1.815n   97.061m/3.068n   0.345/0.973n
R_load = 50.000
[Rising Waveform]
R_fixture= 50.000
V_fixture= 0.0
V_fixture_min= 0.0
V_fixture_max= 0.0
|time   V(typ)   V(min)   V(max)
0s        4.561nV    56.64nV    2.182nV
1.465ns   50.02uV    14.72uV    -365.4uV
2.021ns   -6.09mV    66.79uV    249.7mV
2.268ns   -5.481mV   192.8uV    316.9mV
3.298ns   11.52mV    -406uV     385.1mV
4.167ns   135.5mV    -3.35mV    392.6mV
5.029ns   179.6mV    -857.6uV   394.3mV
6.765ns   191.1mV    4.113mV    394.8mV
9.859ns   192.3mV    106.6mV    394.8mV
20ns      192.4mV    114.9mV    394.9mV
[Rising Waveform]
R_fixture= 50.000
V_fixture= 1.200
V_fixture_min= 1.140
V_fixture_max= 1.260
|time   V(typ)   V(min)   V(max)
0s        873.8mV    978mV      685.5mV
883ps     873.9mV    978mV      679.3mV
1.076ns   873.8mV    978mV      969.6mV
1.21ns    873.7mV    978mV      1.086V
1.799ns   864.2mV    978mV      1.237V
2.051ns   1.024V     977.9mV    1.252V
2.544ns   1.163V     978mV      1.26V
3.849ns   1.195V     1.033V     1.263V
4.815ns   1.199V     1.132V     1.263V
20ns      1.2V       1.14V      1.263V
[Falling Waveform]
R_fixture= 50.000
V_fixture= 1.200
V_fixture_min= 1.140
V_fixture_max= 1.260
|time   V(typ)   V(min)   V(max)
0s        1.2V       1.14V      1.263V
1.039ns   1.2V       1.14V      1.286V
1.612ns   1.2V       1.14V      1.252V
2.787ns   1.201V     1.14V      823.6mV
3.278ns   1.199V     1.14V      747.3mV
4.097ns   1.139V     1.151V     701.1mV
5.672ns   954.2mV    1.14V      686.6mV
7.194ns   893.6mV    1.135V     685.7mV
11.57ns   874.1mV    1.006V     685.5mV
20ns      873.8mV    978.2mV    685.5mV
[Falling Waveform]
R_fixture= 50.000
V_fixture= 0.0
V_fixture_min= 0.0
V_fixture_max= 0.0
|time   V(typ)   V(min)   V(max)
0s        192.4mV    114.9mV    394.9mV
915ps     192.4mV    115mV      396.2mV
1.261ns   192.4mV    115mV      112.7mV
1.925ns   190.8mV    115mV      13mV
2.14ns    101.8mV    115mV      5.786mV
2.814ns   13.43mV    115mV      1.051mV
3.822ns   3.159mV    116.2mV    155.3uV
4.462ns   1.513mV    22.98mV    85.85uV
5.155ns   679.7uV    4.118mV    38.63uV
20ns      6.486nV    905.9nV    -6.471nV
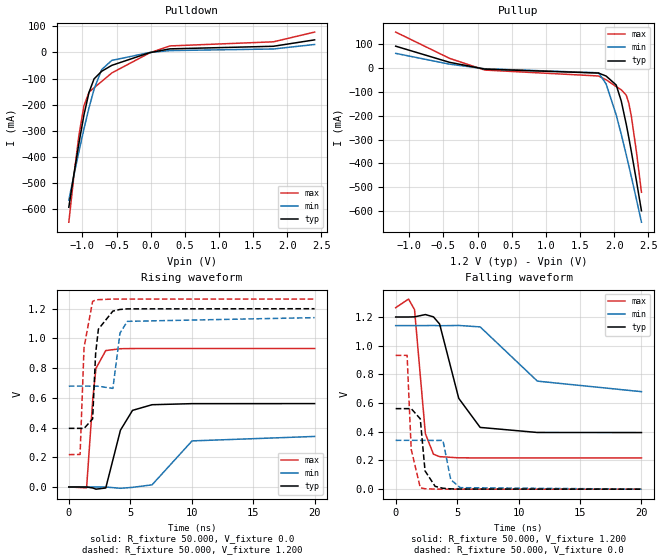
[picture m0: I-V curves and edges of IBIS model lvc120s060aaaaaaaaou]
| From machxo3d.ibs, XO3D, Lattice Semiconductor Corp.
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|   Model lvc120s060aaaaaaaaou
[Model] lvc120s060aaaaaaaaou
Model_type Output
Polarity   Non-Inverting
Enable   Active-High
Vmeas =  0.600V
Cref =  0.0F
Rref =  1.000M
Vref =  0.0V
C_comp   4.200pF   3.800pF   7.500pF
[Temperature Range]   25.000   0.105k   -40.000
[Voltage Range]   1.200V   1.140V   1.260V
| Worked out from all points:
|   slope of the pulldown table from 0 to 0.18 V, typ, clamps not added: 18.4 ohm
|   slope of the pullup table from 0 to 0.18 V, typ, clamps not added: 28.4 ohm
|   rising waveform, R_fixture 50.000, V_fixture 0.0: 20-80 % time 1.03ns typ, 1.88ns min, 470ps max; typ from 0 V to 0.561 V
|   rising waveform, R_fixture 50.000, V_fixture 1.200: 20-80 % time 365ps typ, 413ps min, 386ps max; typ from 0.395 V to 1.2 V
|   falling waveform, R_fixture 50.000, V_fixture 1.200: 20-80 % time 1.59ns typ, 3.21ns min, 575ps max; typ from 1.2 V to 0.395 V
|   falling waveform, R_fixture 50.000, V_fixture 0.0: 20-80 % time 401ps typ, 468ps min, 381ps max; typ from 0.561 V to 0 V
[Pulldown]
|Voltage   I(typ)   I(min)   I(max)
-1.2V     -591.8mA   -564.5mA   -649mA
-1.126V   -466.6mA   -470.4mA   -473.7mA
-1.052V   -347.3mA   -379.1mA   -316.6mA
-978mV    -238.8mA   -292mA     -203.7mA
-904mV    -152.5mA   -211.3mA   -152.2mA
-830mV    -101.2mA   -140.6mA   -135.1mA
-719mV    -72.26mA   -65.9mA    -111.2mA
-571mV    -49.64mA   -30.71mA   -78.72mA
-16mV     -1.08mA    -574.4uA   -1.961mA
280mV     13.4mA     6.806mA    24.65mA
1.797V    23.32mA    12.96mA    40.33mA
2.4V      47.8mA     30.13mA    77.52mA
[Pullup]
|Voltage   I(typ)   I(min)   I(max)
-1.2V     92.36mA    62.18mA    151.6mA
-412mV    24.6mA     16.87mA    41.32mA
106mV     -4.067mA   -2.584mA   -8.006mA
1.771V    -20.72mA   -19.46mA   -32.89mA
1.882V    -33.01mA   -66.14mA   -48.76mA
2.03V     -70.74mA   -196.6mA   -77.4mA
2.104V    -138.2mA   -278mA     -90.83mA
2.178V    -236.9mA   -365.4mA   -114mA
2.215V    -292.6mA   -410.8mA   -147.3mA
2.252V    -350.9mA   -456.9mA   -202.2mA
2.326V    -473mA     -551.2mA   -350.5mA
2.4V      -599.8mA   -647.5mA   -521.7mA
[Ramp]
| variable   typ   min   max
dV/dt_r   0.337/1.029n   0.204/1.849n   0.559/0.468n
dV/dt_f   0.483/1.581n   0.276/3.159n   0.628/0.576n
R_load = 50.000
[Rising Waveform]
R_fixture= 50.000
V_fixture= 0.0
V_fixture_min= 0.0
V_fixture_max= 0.0
|time   V(typ)   V(min)   V(max)
0s        2.29nV     33nV       1nV
1.446ns   -136.3uV   6.559uV    -5.769mV
1.959ns   -6.909mV   31.56uV    601.1mV
2.21ns    -14.67mV   31.56uV    798.9mV
3.006ns   -6.692mV   -314.9uV   918.3mV
4.201ns   382.3mV    -8.762mV   930.8mV
5.185ns   515.8mV    -2.571mV   932mV
6.774ns   553.8mV    14.59mV    932.2mV
10.03ns   561mV      310.2mV    932.2mV
20ns      561.3mV    340.2mV    932.2mV
[Rising Waveform]
R_fixture= 50.000
V_fixture= 1.200
V_fixture_min= 1.140
V_fixture_max= 1.260
|time   V(typ)   V(min)   V(max)
0s        394.7mV    678.9mV    217.9mV
916ps     394.7mV    678.9mV    219mV
1.239ns   394.2mV    678.9mV    938.9mV
1.938ns   458.2mV    678.7mV    1.25V
2.181ns   898.3mV    678.2mV    1.258V
2.405ns   1.062V     678.1mV    1.261V
3.587ns   1.184V     663.8mV    1.265V
4.164ns   1.195V     1.036V     1.265V
4.767ns   1.199V     1.115V     1.265V
20ns      1.2V       1.14V      1.265V
[Falling Waveform]
R_fixture= 50.000
V_fixture= 1.200
V_fixture_min= 1.140
V_fixture_max= 1.260
|time   V(typ)   V(min)   V(max)
0s        1.2V       1.14V      1.265V
1.045ns   1.2V       1.14V      1.325V
1.534ns   1.201V     1.14V      1.251V
2.416ns   1.217V     1.14V      386.4mV
3.073ns   1.201V     1.141V     243.7mV
3.574ns   1.151V     1.139V     226.7mV
5.131ns   633mV      1.141V     218.3mV
6.874ns   430.4mV    1.131V     218mV
11.53ns   395.1mV    753mV      217.9mV
20ns      394.7mV    679.6mV    217.9mV
[Falling Waveform]
R_fixture= 50.000
V_fixture= 0.0
V_fixture_min= 0.0
V_fixture_max= 0.0
|time   V(typ)   V(min)   V(max)
0s        561.3mV    340.2mV    932.2mV
927ps     561.4mV    340.3mV    933mV
1.263ns   561.3mV    340.3mV    277.6mV
2ns       490.4mV    340.3mV    9.923mV
2.387ns   127.6mV    340.3mV    2.856mV
3.207ns   19.65mV    339.3mV    409.8uV
3.843ns   6.28mV     340.3mV    107.6uV
4.479ns   2.104mV    66.35mV    52.42uV
5.251ns   729.5uV    10.51mV    18.83uV
20ns      6.126nV    1.109uV    15.51nV
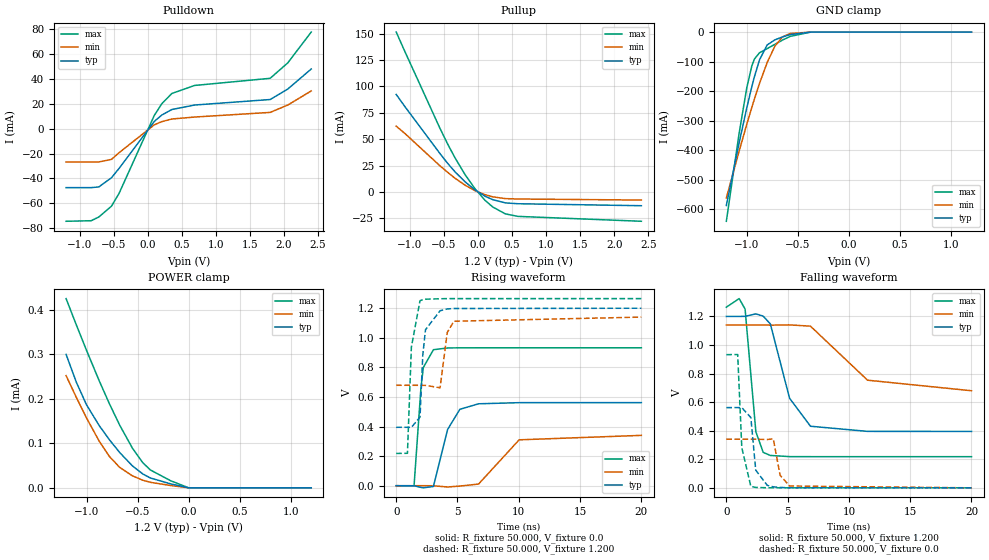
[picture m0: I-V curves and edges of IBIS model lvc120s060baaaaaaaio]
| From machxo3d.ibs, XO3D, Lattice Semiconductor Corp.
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|   Model lvc120s060baaaaaaaio
[Model] lvc120s060baaaaaaaio
Model_type I/O
Polarity   Non-Inverting
Enable   Active-Low
Vinl =  0.420V
Vinh =  0.780V
Vmeas =  0.600V
Cref =  0.0F
Rref =  1.000M
Vref =  0.0V
C_comp   4.200pF   3.800pF   7.500pF
[Temperature Range]   25.000   0.105k   -40.000
[Voltage Range]   1.200V   1.140V   1.260V
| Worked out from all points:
|   slope of the pulldown table from 0 to 0.18 V, typ, clamps not added: 18.4 ohm
|   slope of the pullup table from 0 to 0.18 V, typ, clamps not added: 28.4 ohm
|   GND clamp passes 1 mA (typ) near -0.44 V on its own axis
|   rising waveform, R_fixture 50.000, V_fixture 0.0: 20-80 % time 1.03ns typ, 1.86ns min, 471ps max; typ from 0 V to 0.562 V
|   rising waveform, R_fixture 50.000, V_fixture 1.200: 20-80 % time 365ps typ, 413ps min, 388ps max; typ from 0.395 V to 1.2 V
|   falling waveform, R_fixture 50.000, V_fixture 1.200: 20-80 % time 1.61ns typ, 3.22ns min, 579ps max; typ from 1.2 V to 0.395 V
|   falling waveform, R_fixture 50.000, V_fixture 0.0: 20-80 % time 404ps typ, 470ps min, 386ps max; typ from 0.562 V to 0 V
[Pulldown]
|Voltage   I(typ)   I(min)   I(max)
-1.2V     -47.32mA   -26.76mA   -74.28mA
-830mV    -47.32mA   -26.76mA   -73.83mA
-719mV    -46.75mA   -26.76mA   -70.83mA
-534mV    -39.41mA   -24.7mA    -62.22mA
-423mV    -32.02mA   -19.39mA   -52.05mA
95mV      5.729mA    2.992mA    10.49mA
206mV     10.86mA    5.583mA    19.95mA
354mV     15.29mA    7.674mA    28.14mA
687mV     18.86mA    9.24mA     34.55mA
1.797V    23.28mA    12.96mA    40.28mA
2.056V    31.71mA    18.88mA    52.68mA
2.4V      47.74mA    30.18mA    77.35mA
[Pullup]
|Voltage   I(typ)   I(min)   I(max)
-1.2V     92.32mA    62.26mA    151.4mA
-1.078V   81.33mA    55.7mA     133.7mA
-560mV    36.56mA    24.91mA    60.6mA
-449mV    27.44mA    18.84mA    45.93mA
-338mV    19.2mA     13.09mA    32.47mA
-190mV    9.687mA    6.463mA    16.55mA
-42mV     1.884mA    1.222mA    2.939mA
106mV     -4.067mA   -2.584mA   -8.006mA
217mV     -7.275mA   -4.565mA   -14.19mA
402mV     -10.32mA   -6.287mA   -20.71mA
587mV     -11.14mA   -6.66mA    -23.11mA
2.4V      -13.01mA   -7.654mA   -27.74mA
[GND_clamp]
|Voltage   I(typ)   I(min)   I(max)
-1.2V     -586.8mA   -561.6mA   -640.3mA
-1.075V   -375.3mA   -403.2mA   -342.9mA
-1V       -256.8mA   -312.3mA   -188.8mA
-950mV    -184.3mA   -254.5mA   -114mA
-925mV    -151.1mA   -226.6mA   -91.27mA
-875mV    -93.95mA   -173.6mA   -70mA
-800mV    -43.51mA   -102.9mA   -56.05mA
-725mV    -26.4mA    -48.03mA   -41.58mA
-650mV    -16.51mA   -16.35mA   -27.17mA
-575mV    -8.674mA   -5.016mA   -14.71mA
-375mV    -194.8uA   -87.66uA   -296.2uA
1.2V      -42.59nA   0A         -5.33uA
[POWER_clamp]
|Voltage   I(typ)   I(min)   I(max)
-1.2V     299.6uA    251.9uA    424.8uA
-1.1V     237.3uA    203.2uA    366uA
-1V       186.4uA    156.9uA    308.7uA
-875mV    139.5uA    104.5uA    239.9uA
-775mV    107.7uA    70.18uA    188.3uA
-675mV    79.18uA    45.9uA     140.6uA
-550mV    49.19uA    26.84uA    88.83uA
-450mV    31.3uA     17.16uA    56.66uA
-375mV    22.16uA    12.38uA    40.11uA
-175mV    8.775uA    5.159uA    15.8uA
0V        3.648nA    7.361nA    0A
1.2V      0A         0A         0A
[Ramp]
| variable   typ   min   max
dV/dt_r   0.337/1.027n   0.204/1.837n   0.559/0.469n
dV/dt_f   0.483/1.574n   0.276/3.155n   0.628/0.578n
R_load = 50.000
[Rising Waveform]
R_fixture= 50.000
V_fixture= 0.0
V_fixture_min= 0.0
V_fixture_max= 0.0
|time   V(typ)   V(min)   V(max)
0s        138.6uV    95.1uV     209.2uV
1.455ns   -240.6uV   102.4uV    -1.688mV
2.012ns   -11.11mV   127.2uV    655.1mV
2.21ns    -14.27mV   190.3uV    798.8mV
3.035ns   -5.229mV   -251.2uV   919.5mV
4.191ns   379.7mV    -8.638mV   931.3mV
5.193ns   516.6mV    -2.312mV   932.4mV
6.719ns   553.9mV    11.35mV    932.6mV
10.03ns   561.5mV    310.3mV    932.6mV
20ns      561.8mV    340.4mV    932.6mV
[Rising Waveform]
R_fixture= 50.000
V_fixture= 1.200
V_fixture_min= 1.140
V_fixture_max= 1.260
|time   V(typ)   V(min)   V(max)
0s        395.1mV    679.1mV    218.3mV
916ps     395.1mV    679.2mV    219.3mV
1.238ns   394.5mV    679.1mV    937.2mV
1.942ns   464.2mV    678.9mV    1.251V
2.167ns   881.2mV    678.6mV    1.258V
2.39ns    1.055V     678.3mV    1.261V
3.579ns   1.183V     662.2mV    1.264V
4.164ns   1.195V     1.036V     1.265V
4.708ns   1.198V     1.112V     1.265V
20ns      1.2V       1.14V      1.265V
[Falling Waveform]
R_fixture= 50.000
V_fixture= 1.200
V_fixture_min= 1.140
V_fixture_max= 1.260
|time   V(typ)   V(min)   V(max)
0s        1.2V       1.14V      1.265V
1.045ns   1.2V       1.14V      1.325V
1.53ns    1.201V     1.14V      1.252V
2.409ns   1.218V     1.14V      392.4mV
3.009ns   1.202V     1.141V     248.4mV
3.59ns    1.148V     1.139V     226.8mV
5.156ns   627.8mV    1.141V     218.6mV
6.864ns   431.3mV    1.132V     218.3mV
11.52ns   395.4mV    753.8mV    218.2mV
20ns      395mV      679.9mV    218.2mV
[Falling Waveform]
R_fixture= 50.000
V_fixture= 0.0
V_fixture_min= 0.0
V_fixture_max= 0.0
|time   V(typ)   V(min)   V(max)
0s        561.8mV    340.5mV    932.6mV
927ps     561.9mV    340.6mV    933.4mV
1.262ns   561.8mV    340.6mV    280.9mV
1.999ns   492.2mV    340.5mV    10.52mV
2.399ns   123.8mV    340.4mV    2.977mV
3.342ns   17.07mV    338.5mV    599.7uV
3.83ns    6.921mV    342.7mV    381.7uV
4.388ns   2.751mV    87.81mV    255.2uV
5.163ns   1.025mV    12.87mV    224.7uV
20ns      138.6uV    96.22uV    209.2uV
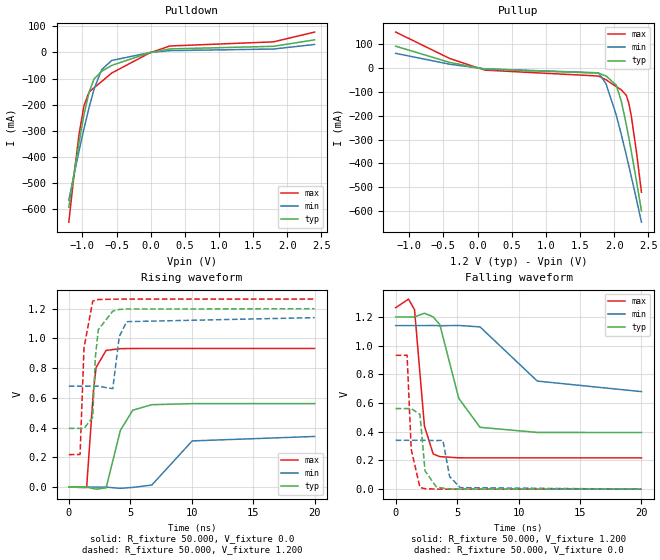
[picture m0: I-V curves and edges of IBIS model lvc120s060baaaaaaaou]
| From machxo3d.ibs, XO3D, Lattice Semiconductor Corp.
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|   Model lvc120s060baaaaaaaou
[Model] lvc120s060baaaaaaaou
Model_type Output
Polarity   Non-Inverting
Enable   Active-High
Vmeas =  0.600V
Cref =  0.0F
Rref =  1.000M
Vref =  0.0V
C_comp   4.200pF   3.800pF   7.500pF
[Temperature Range]   25.000   0.105k   -40.000
[Voltage Range]   1.200V   1.140V   1.260V
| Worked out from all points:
|   slope of the pulldown table from 0 to 0.18 V, typ, clamps not added: 18.4 ohm
|   slope of the pullup table from 0 to 0.18 V, typ, clamps not added: 28.4 ohm
|   rising waveform, R_fixture 50.000, V_fixture 0.0: 20-80 % time 1.04ns typ, 1.85ns min, 469ps max; typ from 0 V to 0.562 V
|   rising waveform, R_fixture 50.000, V_fixture 1.200: 20-80 % time 365ps typ, 415ps min, 384ps max; typ from 0.395 V to 1.2 V
|   falling waveform, R_fixture 50.000, V_fixture 1.200: 20-80 % time 1.61ns typ, 3.16ns min, 575ps max; typ from 1.2 V to 0.395 V
|   falling waveform, R_fixture 50.000, V_fixture 0.0: 20-80 % time 403ps typ, 470ps min, 383ps max; typ from 0.562 V to 0 V
[Pulldown]
|Voltage   I(typ)   I(min)   I(max)
-1.2V     -591.8mA   -564.5mA   -649mA
-1.126V   -466.6mA   -470.4mA   -473.7mA
-1.052V   -347.3mA   -379.1mA   -316.6mA
-978mV    -238.8mA   -292mA     -203.7mA
-904mV    -152.5mA   -211.3mA   -152.2mA
-830mV    -101.2mA   -140.6mA   -135.1mA
-719mV    -72.27mA   -65.9mA    -111.2mA
-571mV    -49.64mA   -30.72mA   -78.74mA
-16mV     -1.092mA   -579.7uA   -1.991mA
280mV     13.38mA    6.801mA    24.62mA
1.797V    23.34mA    13mA       40.36mA
2.4V      48.04mA    30.47mA    77.74mA
[Pullup]
|Voltage   I(typ)   I(min)   I(max)
-1.2V     92.62mA    62.51mA    151.9mA
-412mV    24.62mA    16.88mA    41.35mA
106mV     -4.071mA   -2.587mA   -8.015mA
1.771V    -20.72mA   -19.45mA   -32.9mA
1.882V    -33.02mA   -66.15mA   -48.77mA
2.03V     -70.75mA   -196.6mA   -77.4mA
2.104V    -138.2mA   -278mA     -90.83mA
2.178V    -236.9mA   -365.4mA   -114mA
2.215V    -292.6mA   -410.8mA   -147.4mA
2.252V    -350.9mA   -456.9mA   -202.3mA
2.326V    -473mA     -551.2mA   -350.5mA
2.4V      -599.8mA   -647.5mA   -521.7mA
[Ramp]
| variable   typ   min   max
dV/dt_r   0.337/1.030n   0.204/1.837n   0.559/0.468n
dV/dt_f   0.483/1.581n   0.276/3.151n   0.628/0.577n
R_load = 50.000
[Rising Waveform]
R_fixture= 50.000
V_fixture= 0.0
V_fixture_min= 0.0
V_fixture_max= 0.0
|time   V(typ)   V(min)   V(max)
0s        138.6uV    95.11uV    209.2uV
1.449ns   -5.293uV   101.3uV    -3.638mV
2.001ns   -10.39mV   126.2uV    645.6mV
2.219ns   -14.1mV    181.8uV    804.3mV
3.035ns   -5.223mV   -253.1uV   919.6mV
4.195ns   381.3mV    -8.661mV   931.2mV
5.201ns   517.3mV    -2.307mV   932.5mV
6.755ns   554.2mV    13.63mV    932.6mV
10.04ns   561.5mV    310.6mV    932.6mV
20ns      561.8mV    340.5mV    932.6mV
[Rising Waveform]
R_fixture= 50.000
V_fixture= 1.200
V_fixture_min= 1.140
V_fixture_max= 1.260
|time   V(typ)   V(min)   V(max)
0s        395.1mV    679.1mV    218.3mV
916ps     395.1mV    679.2mV    219.3mV
1.236ns   394.5mV    679.1mV    936.5mV
1.946ns   470.1mV    678.9mV    1.251V
2.163ns   876.1mV    678.6mV    1.258V
2.4ns     1.059V     678.3mV    1.262V
3.579ns   1.184V     662.2mV    1.264V
4.107ns   1.195V     1.013V     1.265V
4.707ns   1.198V     1.113V     1.265V
20ns      1.2V       1.14V      1.265V
[Falling Waveform]
R_fixture= 50.000
V_fixture= 1.200
V_fixture_min= 1.140
V_fixture_max= 1.260
|time   V(typ)   V(min)   V(max)
0s        1.2V       1.14V      1.265V
1.045ns   1.2V       1.14V      1.325V
1.534ns   1.201V     1.14V      1.251V
2.339ns   1.226V     1.14V      440.1mV
3.051ns   1.201V     1.141V     245.4mV
3.59ns    1.147V     1.139V     227mV
5.135ns   632.6mV    1.141V     218.6mV
6.864ns   431.1mV    1.131V     218.3mV
11.52ns   395.6mV    753.5mV    218.3mV
20ns      395mV      679.9mV    218.2mV
[Falling Waveform]
R_fixture= 50.000
V_fixture= 0.0
V_fixture_min= 0.0
V_fixture_max= 0.0
|time   V(typ)   V(min)   V(max)
0s        561.8mV    340.5mV    932.6mV
927ps     561.9mV    340.6mV    933.4mV
1.265ns   561.8mV    340.6mV    277.3mV
1.973ns   521.3mV    340.5mV    11.74mV
2.387ns   128.2mV    340.5mV    3.099mV
3.287ns   18.05mV    338.9mV    637.5uV
3.843ns   6.662mV    340.5mV    326uV
4.387ns   2.616mV    87.95mV    268uV
5.252ns   938.1uV    10.69mV    231.6uV
20ns      138.6uV    96.22uV    209.2uV
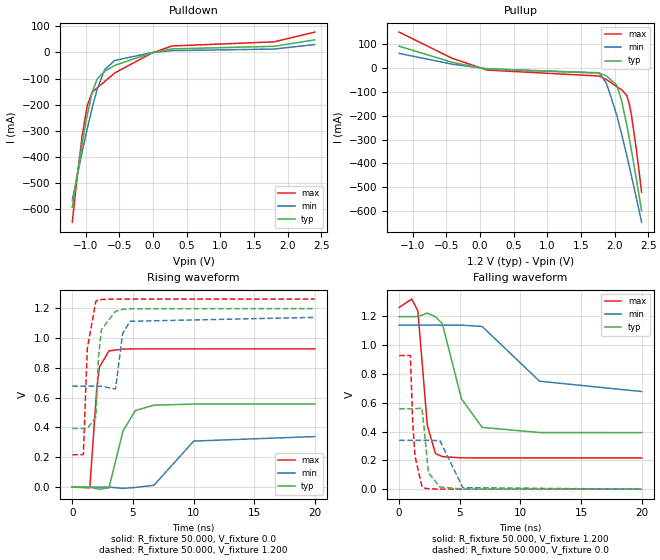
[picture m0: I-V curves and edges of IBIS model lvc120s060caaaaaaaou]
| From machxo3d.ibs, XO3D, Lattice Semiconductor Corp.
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|   Model lvc120s060caaaaaaaou
[Model] lvc120s060caaaaaaaou
Model_type Output
Polarity   Non-Inverting
Enable   Active-High
Vmeas =  0.600V
Cref =  0.0F
Rref =  1.000M
Vref =  0.0V
C_comp   4.200pF   3.800pF   7.500pF
[Temperature Range]   25.000   0.105k   -40.000
[Voltage Range]   1.200V   1.140V   1.260V
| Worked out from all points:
|   slope of the pulldown table from 0 to 0.18 V, typ, clamps not added: 18.3 ohm
|   slope of the pullup table from 0 to 0.18 V, typ, clamps not added: 28.4 ohm
|   rising waveform, R_fixture 50.000, V_fixture 0.0: 20-80 % time 1.03ns typ, 1.84ns min, 473ps max; typ from 0 V to 0.557 V
|   rising waveform, R_fixture 50.000, V_fixture 1.200: 20-80 % time 370ps typ, 417ps min, 401ps max; typ from 0.393 V to 1.2 V
|   falling waveform, R_fixture 50.000, V_fixture 1.200: 20-80 % time 1.59ns typ, 3.23ns min, 574ps max; typ from 1.2 V to 0.393 V
|   falling waveform, R_fixture 50.000, V_fixture 0.0: 20-80 % time 391ps typ, 468ps min, 369ps max; typ from 0.557 V to 0 V
[Pulldown]
|Voltage   I(typ)   I(min)   I(max)
-1.2V     -591.8mA   -564.5mA   -649mA
-1.126V   -466.6mA   -470.4mA   -473.8mA
-1.052V   -347.3mA   -379.1mA   -316.6mA
-978mV    -238.8mA   -292mA     -203.8mA
-904mV    -152.6mA   -211.3mA   -152.3mA
-830mV    -101.2mA   -140.6mA   -135.2mA
-719mV    -72.31mA   -65.93mA   -111.3mA
-571mV    -49.7mA    -30.76mA   -78.81mA
-16mV     -1.084mA   -576.1uA   -1.969mA
280mV     13.45mA    6.829mA    24.77mA
1.797V    23.39mA    13mA       40.48mA
2.4V      47.96mA    30.21mA    77.79mA
[Pullup]
|Voltage   I(typ)   I(min)   I(max)
-1.2V     92.54mA    62.27mA    151.9mA
-412mV    24.69mA    16.91mA    41.52mA
106mV     -3.969mA   -2.548mA   -7.771mA
1.771V    -20.76mA   -19.48mA   -32.97mA
1.882V    -33.04mA   -66.17mA   -48.81mA
2.03V     -70.79mA   -196.6mA   -77.42mA
2.104V    -138.2mA   -278mA     -90.85mA
2.178V    -237mA     -365.4mA   -114mA
2.215V    -292.6mA   -410.8mA   -147.4mA
2.252V    -351mA     -456.9mA   -202.3mA
2.326V    -473mA     -551.2mA   -350.6mA
2.4V      -599.8mA   -647.5mA   -521.8mA
[Ramp]
| variable   typ   min   max
dV/dt_r   0.334/1.019n   0.203/1.820n   0.557/0.471n
dV/dt_f   0.483/1.576n   0.277/3.177n   0.627/0.576n
R_load = 50.000
[Rising Waveform]
R_fixture= 50.000
V_fixture= 0.0
V_fixture_min= 0.0
V_fixture_max= 0.0
|time   V(typ)   V(min)   V(max)
0s        2.212nV    32.68nV    920.7pV
1.446ns   -134uV     5.554uV    -5.42mV
2.011ns   -11.25mV   30.46uV    649.8mV
2.23ns    -14.08mV   98.62uV    802.9mV
3.025ns   -6.059mV   -354.1uV   914.1mV
4.19ns    377.4mV    -8.804mV   926.4mV
5.202ns   513.5mV    -2.54mV    927.6mV
6.739ns   549.8mV    12.34mV    927.8mV
10.02ns   557.1mV    308.8mV    927.8mV
20ns      557.4mV    339mV      927.8mV
[Rising Waveform]
R_fixture= 50.000
V_fixture= 1.200
V_fixture_min= 1.140
V_fixture_max= 1.260
|time   V(typ)   V(min)   V(max)
0s        392.9mV    677.3mV    216.8mV
916ps     392.9mV    677.4mV    217.9mV
1.236ns   392.4mV    677.4mV    928.7mV
1.947ns   469.1mV    677.1mV    1.248V
2.166ns   876.1mV    676.8mV    1.256V
2.404ns   1.057V     676.5mV    1.259V
3.567ns   1.18V      658mV      1.262V
4.152ns   1.193V     1.03V      1.262V
4.768ns   1.197V     1.113V     1.262V
20ns      1.198V     1.139V     1.262V
[Falling Waveform]
R_fixture= 50.000
V_fixture= 1.200
V_fixture_min= 1.140
V_fixture_max= 1.260
|time   V(typ)   V(min)   V(max)
0s        1.198V     1.139V     1.262V
1.041ns   1.198V     1.139V     1.32V
1.543ns   1.199V     1.139V     1.237V
2.328ns   1.222V     1.139V     440.2mV
3ns       1.197V     1.14V      246.6mV
3.566ns   1.148V     1.138V     225.8mV
5.139ns   627.2mV    1.139V     217.3mV
6.845ns   429.2mV    1.13V      216.9mV
11.58ns   393.1mV    749.6mV    216.9mV
20ns      392.7mV    678.1mV    216.8mV
[Falling Waveform]
R_fixture= 50.000
V_fixture= 0.0
V_fixture_min= 0.0
V_fixture_max= 0.0
|time   V(typ)   V(min)   V(max)
0s        557.4mV    339mV      927.8mV
927ps     557.5mV    339.1mV    928.4mV
1.117ns   557.4mV    339.1mV    470.9mV
1.313ns   557.4mV    339.1mV    227.2mV
1.885ns   563.8mV    339mV      17.62mV
2.023ns   452.4mV    339mV      8.488mV
2.416ns   113.3mV    339mV      2.537mV
3.361ns   15.11mV    336.9mV    300.7uV
5.256ns   734.8uV    10.17mV    22.05uV
20ns      3.207nV    1.103uV    11.08nV
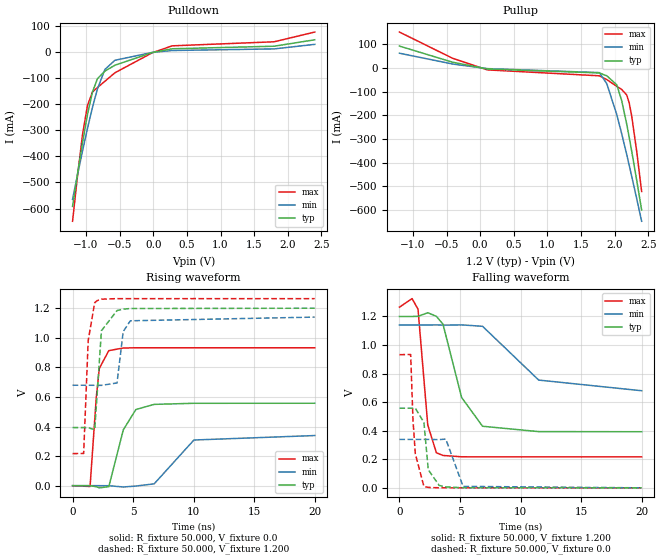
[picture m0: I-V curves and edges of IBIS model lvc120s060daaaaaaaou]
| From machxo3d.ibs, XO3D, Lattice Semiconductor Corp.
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|   Model lvc120s060daaaaaaaou
[Model] lvc120s060daaaaaaaou
Model_type Output
Polarity   Non-Inverting
Enable   Active-High
Vmeas =  0.600V
Cref =  0.0F
Rref =  1.000M
Vref =  0.0V
C_comp   4.200pF   3.800pF   7.500pF
[Temperature Range]   25.000   0.105k   -40.000
[Voltage Range]   1.200V   1.140V   1.260V
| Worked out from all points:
|   slope of the pulldown table from 0 to 0.18 V, typ, clamps not added: 18.3 ohm
|   slope of the pullup table from 0 to 0.18 V, typ, clamps not added: 28.4 ohm
|   rising waveform, R_fixture 50.000, V_fixture 0.0: 20-80 % time 1.02ns typ, 1.84ns min, 479ps max; typ from 0 V to 0.557 V
|   rising waveform, R_fixture 50.000, V_fixture 1.200: 20-80 % time 370ps typ, 412ps min, 403ps max; typ from 0.393 V to 1.2 V
|   falling waveform, R_fixture 50.000, V_fixture 1.200: 20-80 % time 1.61ns typ, 3.22ns min, 577ps max; typ from 1.2 V to 0.393 V
|   falling waveform, R_fixture 50.000, V_fixture 0.0: 20-80 % time 396ps typ, 468ps min, 381ps max; typ from 0.557 V to 0 V
[Pulldown]
|Voltage   I(typ)   I(min)   I(max)
-1.2V     -591.8mA   -564.5mA   -649mA
-1.126V   -466.6mA   -470.4mA   -473.8mA
-1.052V   -347.3mA   -379.1mA   -316.6mA
-978mV    -238.8mA   -292mA     -203.8mA
-904mV    -152.6mA   -211.3mA   -152.3mA
-830mV    -101.2mA   -140.6mA   -135.2mA
-719mV    -72.31mA   -65.93mA   -111.3mA
-571mV    -49.7mA    -30.76mA   -78.81mA
-16mV     -1.084mA   -576.1uA   -1.969mA
280mV     13.45mA    6.829mA    24.77mA
1.797V    23.34mA    13mA       40.36mA
2.4V      48.04mA    30.47mA    77.74mA
[Pullup]
|Voltage   I(typ)   I(min)   I(max)
-1.2V     92.62mA    62.51mA    151.9mA
-412mV    24.62mA    16.88mA    41.35mA
106mV     -4.071mA   -2.587mA   -8.015mA
1.771V    -20.76mA   -19.48mA   -32.97mA
1.882V    -33.04mA   -66.17mA   -48.81mA
2.03V     -70.79mA   -196.6mA   -77.42mA
2.104V    -138.2mA   -278mA     -90.85mA
2.178V    -237mA     -365.4mA   -114mA
2.215V    -292.6mA   -410.8mA   -147.4mA
2.252V    -351mA     -456.9mA   -202.3mA
2.326V    -473mA     -551.2mA   -350.6mA
2.4V      -599.8mA   -647.5mA   -521.8mA
[Ramp]
| variable   typ   min   max
dV/dt_r   0.334/1.019n   0.203/1.820n   0.560/0.476n
dV/dt_f   0.484/1.583n   0.276/3.151n   0.629/0.579n
R_load = 50.000
[Rising Waveform]
R_fixture= 50.000
V_fixture= 0.0
V_fixture_min= 0.0
V_fixture_max= 0.0
|time   V(typ)   V(min)   V(max)
0s        2.212nV    32.68nV    920.7pV
1.446ns   -134uV     6.46uV     -5.42mV
1.961ns   -6.898mV   31.31uV    599.5mV
2.21ns    -14.59mV   31.31uV    793.2mV
2.994ns   -6.818mV   -314.1uV   913.3mV
4.19ns    377.4mV    -8.813mV   930.8mV
5.227ns   514.9mV    -2.538mV   932.5mV
6.739ns   549.8mV    12.34mV    932.6mV
10.02ns   557.1mV    308.8mV    932.6mV
20ns      557.4mV    339mV      932.6mV
[Rising Waveform]
R_fixture= 50.000
V_fixture= 1.200
V_fixture_min= 1.140
V_fixture_max= 1.260
|time   V(typ)   V(min)   V(max)
0s        392.9mV    679.1mV    216.8mV
916ps     392.9mV    679.2mV    217.9mV
1.291ns   392.4mV    679.1mV    981.1mV
1.827ns   378mV      678.9mV    1.237V
2.016ns   601.3mV    678.6mV    1.251V
2.384ns   1.048V     678.3mV    1.261V
3.671ns   1.184V     694.7mV    1.265V
4.182ns   1.194V     1.042V     1.265V
4.768ns   1.198V     1.115V     1.265V
20ns      1.2V       1.14V      1.265V
[Falling Waveform]
R_fixture= 50.000
V_fixture= 1.200
V_fixture_min= 1.140
V_fixture_max= 1.260
|time   V(typ)   V(min)   V(max)
0s        1.2V       1.14V      1.265V
1.045ns   1.2V       1.14V      1.325V
1.534ns   1.201V     1.14V      1.251V
2.339ns   1.226V     1.14V      440.1mV
3.051ns   1.201V     1.141V     245.4mV
3.6ns     1.145V     1.139V     226.7mV
5.135ns   632.6mV    1.141V     217.3mV
6.864ns   431.1mV    1.131V     216.9mV
11.5ns    393.7mV    754.5mV    216.8mV
20ns      392.8mV    679.9mV    216.8mV
[Falling Waveform]
R_fixture= 50.000
V_fixture= 0.0
V_fixture_min= 0.0
V_fixture_max= 0.0
|time   V(typ)   V(min)   V(max)
0s        557.4mV    339mV      932.6mV
927ps     557.5mV    339.1mV    933.4mV
1.118ns   557.4mV    339.1mV    478.2mV
1.311ns   557.4mV    339.1mV    238.3mV
2.022ns   458.1mV    339mV      9.378mV
2.382ns   126.7mV    339mV      3.021mV
3.279ns   17.05mV    337.4mV    385.7uV
3.827ns   6.329mV    341.6mV    169.2uV
5.256ns   734.8uV    10.17mV    14.8uV
20ns      3.207nV    1.103uV    5.879nV
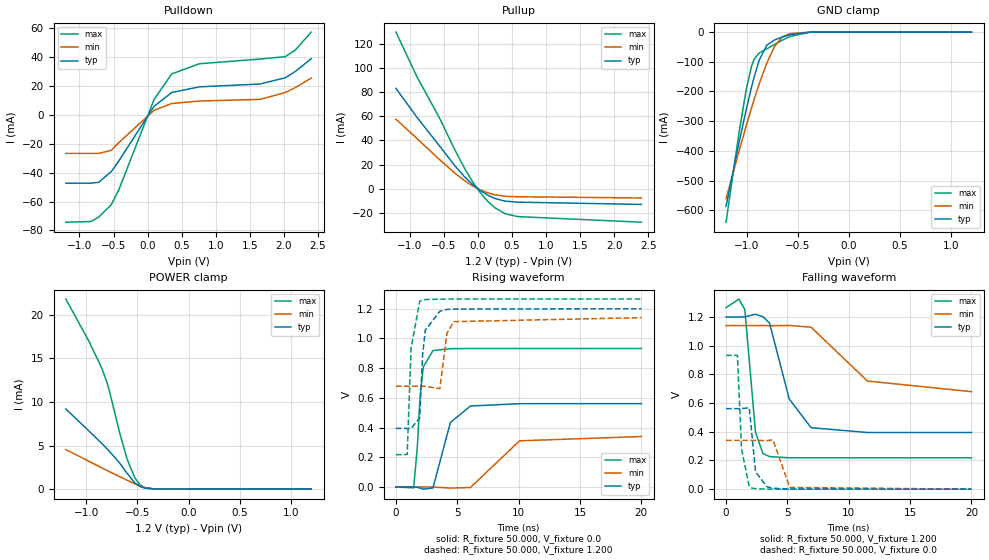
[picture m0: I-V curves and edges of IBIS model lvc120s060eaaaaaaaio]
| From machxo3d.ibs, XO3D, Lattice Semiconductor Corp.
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|   Model lvc120s060eaaaaaaaio
[Model] lvc120s060eaaaaaaaio
Model_type I/O
Polarity   Non-Inverting
Enable   Active-Low
Vinl =  0.420V
Vinh =  0.780V
Vmeas =  0.600V
Cref =  0.0F
Rref =  1.000M
Vref =  0.0V
C_comp   4.200pF   3.800pF   7.500pF
[Temperature Range]   25.000   0.105k   -40.000
[Voltage Range]   1.200V   1.140V   1.260V
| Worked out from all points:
|   slope of the pulldown table from 0 to 0.18 V, typ, clamps not added: 18.4 ohm
|   slope of the pullup table from 0 to 0.18 V, typ, clamps not added: 28.4 ohm
|   GND clamp passes 1 mA (typ) near -0.44 V on its own axis
|   POWER clamp passes 1 mA (typ) near -0.55 V on its own axis
|   rising waveform, R_fixture 50.000, V_fixture 0.0: 20-80 % time 1.03ns typ, 1.88ns min, 472ps max; typ from 0 V to 0.561 V
|   rising waveform, R_fixture 50.000, V_fixture 1.200: 20-80 % time 365ps typ, 416ps min, 388ps max; typ from 0.395 V to 1.2 V
|   falling waveform, R_fixture 50.000, V_fixture 1.200: 20-80 % time 1.6ns typ, 3.16ns min, 582ps max; typ from 1.2 V to 0.395 V
|   falling waveform, R_fixture 50.000, V_fixture 0.0: 20-80 % time 402ps typ, 467ps min, 384ps max; typ from 0.561 V to 0 V
[Pulldown]
|Voltage   I(typ)   I(min)   I(max)
-1.2V     -47.32mA   -26.76mA   -74.28mA
-830mV    -47.32mA   -26.76mA   -73.83mA
-719mV    -46.75mA   -26.76mA   -70.83mA
-534mV    -39.41mA   -24.7mA    -62.22mA
-423mV    -32.02mA   -19.39mA   -52.05mA
95mV      5.729mA    2.992mA    10.49mA
354mV     15.29mA    7.674mA    28.14mA
761mV     19.19mA    9.392mA    35.13mA
1.649V    21.15mA    10.52mA    38.38mA
2.019V    25.44mA    15.26mA    40mA
2.167V    29.79mA    18.68mA    44.62mA
2.4V      38.62mA    25.26mA    57mA
[Pullup]
|Voltage   I(typ)   I(min)   I(max)
-1.2V     83.18mA    57.65mA    129.8mA
-893mV    59.32mA    41.67mA    92.95mA
-560mV    35.41mA    24.12mA    58.49mA
-338mV    19.19mA    13.06mA    32.47mA
-190mV    9.687mA    6.463mA    16.55mA
-79mV     3.668mA    2.398mA    6.116mA
32mV      -1.332mA   -852.4uA   -2.917mA
143mV     -5.255mA   -3.326mA   -10.26mA
254mV     -8.11mA    -5.063mA   -15.86mA
402mV     -10.32mA   -6.287mA   -20.71mA
587mV     -11.14mA   -6.66mA    -23.11mA
2.4V      -13.01mA   -7.654mA   -27.74mA
[GND_clamp]
|Voltage   I(typ)   I(min)   I(max)
-1.2V     -586.8mA   -561.6mA   -640.3mA
-1.075V   -375.3mA   -403.2mA   -342.9mA
-1V       -256.8mA   -312.3mA   -188.8mA
-950mV    -184.3mA   -254.5mA   -114.1mA
-925mV    -151.1mA   -226.6mA   -91.26mA
-875mV    -93.95mA   -173.6mA   -69.99mA
-800mV    -43.5mA    -102.9mA   -56.04mA
-725mV    -26.4mA    -48.03mA   -41.57mA
-650mV    -16.5mA    -16.35mA   -27.16mA
-575mV    -8.667mA   -5.012mA   -14.69mA
-375mV    -183.5uA   -82.46uA   -270.8uA
1.2V      0A         0A         0A
[POWER_clamp]
|Voltage   I(typ)   I(min)   I(max)
-1.2V     9.182mA    4.531mA    21.77mA
-975mV    6.68mA     3.195mA    16.97mA
-850mV    5.256mA    2.452mA    13.9mA
-800mV    4.662mA    2.159mA    12.31mA
-775mV    4.355mA    2.014mA    11.32mA
-675mV    3.015mA    1.438mA    6.52mA
-600mV    1.813mA    1.015mA    3.43mA
-525mV    717.6uA    612.9uA    1.296mA
-475mV    302.2uA    372.2uA    507.9uA
-425mV    111uA      180.2uA    159.4uA
-325mV    13.15uA    20.51uA    12.23uA
1.2V      0A         0A         3.808nA
[Ramp]
| variable   typ   min   max
dV/dt_r   0.337/1.027n   0.204/1.841n   0.559/0.470n
dV/dt_f   0.483/1.577n   0.276/3.164n   0.628/0.577n
R_load = 50.000
[Rising Waveform]
R_fixture= 50.000
V_fixture= 0.0
V_fixture_min= 0.0
V_fixture_max= 0.0
|time   V(typ)   V(min)   V(max)
0s        2.304nV    32.88nV    1.018nV
1.449ns   -206.1uV   6.3uV      -4.866mV
1.748ns   -1.622mV   6.3uV      275.4mV
1.96ns    -6.903mV   31.2uV     601.1mV
2.232ns   -14.13mV   31.2uV     808.5mV
3.016ns   -6.453mV   -337.2uV   918.3mV
4.439ns   434.3mV    -6.297mV   931.4mV
6.069ns   545.3mV    -3.302mV   932.2mV
10.07ns   561mV      311.1mV    932.2mV
20ns      561.3mV    340.2mV    932.3mV
[Rising Waveform]
R_fixture= 50.000
V_fixture= 1.200
V_fixture_min= 1.140
V_fixture_max= 1.260
|time   V(typ)   V(min)   V(max)
0s        394.7mV    678.9mV    217.9mV
916ps     394.7mV    678.9mV    219mV
1.238ns   394.2mV    678.9mV    936.3mV
1.944ns   466.7mV    678.7mV    1.251V
2.164ns   876.8mV    678.2mV    1.258V
2.39ns    1.055V     678mV      1.262V
3.579ns   1.183V     662mV      1.264V
4.162ns   1.195V     1.036V     1.265V
4.712ns   1.198V     1.113V     1.265V
20ns      1.2V       1.14V      1.265V
[Falling Waveform]
R_fixture= 50.000
V_fixture= 1.200
V_fixture_min= 1.140
V_fixture_max= 1.260
|time   V(typ)   V(min)   V(max)
0s        1.2V       1.14V      1.265V
1.045ns   1.2V       1.14V      1.325V
1.53ns    1.201V     1.14V      1.252V
2.399ns   1.219V     1.14V      397.7mV
3.002ns   1.202V     1.141V     248.5mV
3.542ns   1.158V     1.139V     227.3mV
5.151ns   628.4mV    1.141V     218.4mV
6.928ns   428.5mV    1.129V     217.9mV
11.52ns   395.1mV    753.6mV    217.9mV
20ns      394.7mV    679.6mV    217.9mV
[Falling Waveform]
R_fixture= 50.000
V_fixture= 0.0
V_fixture_min= 0.0
V_fixture_max= 0.0
|time   V(typ)   V(min)   V(max)
0s        561.3mV    340.2mV    932.2mV
927ps     561.4mV    340.3mV    933mV
1.262ns   561.3mV    340.3mV    279.4mV
1.886ns   567.7mV    340.3mV    18.91mV
2.026ns   452mV      340.3mV    8.924mV
2.405ns   120.8mV    340.2mV    2.899mV
3.337ns   16.63mV    338.2mV    316uV
3.823ns   6.706mV    343.5mV    126.1uV
5.196ns   883.3uV    11.92mV    25.74uV
20ns      5.319nV    1.111uV    -8.349nV
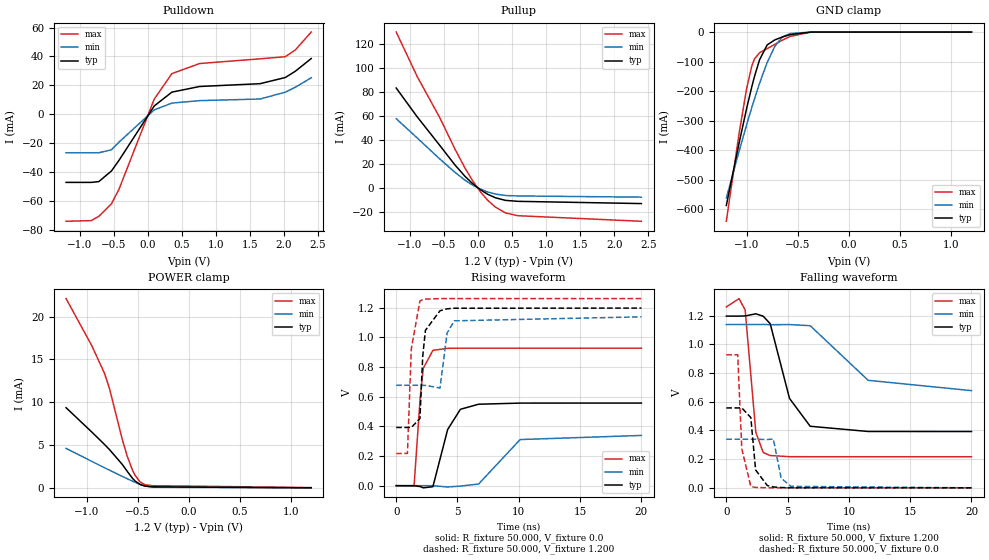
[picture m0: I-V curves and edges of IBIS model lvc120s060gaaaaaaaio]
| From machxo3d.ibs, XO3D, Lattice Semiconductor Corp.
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|   Model lvc120s060gaaaaaaaio
[Model] lvc120s060gaaaaaaaio
Model_type I/O
Polarity   Non-Inverting
Enable   Active-Low
Vinl =  0.420V
Vinh =  0.780V
Vmeas =  0.600V
Cref =  0.0F
Rref =  1.000M
Vref =  0.0V
C_comp   4.200pF   3.800pF   7.500pF
[Temperature Range]   25.000   0.105k   -40.000
[Voltage Range]   1.200V   1.140V   1.260V
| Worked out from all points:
|   slope of the pulldown table from 0 to 0.18 V, typ, clamps not added: 18.4 ohm
|   slope of the pullup table from 0 to 0.18 V, typ, clamps not added: 28.4 ohm
|   GND clamp passes 1 mA (typ) near -0.44 V on its own axis
|   POWER clamp passes 1 mA (typ) near -0.54 V on its own axis
|   rising waveform, R_fixture 50.000, V_fixture 0.0: 20-80 % time 1.04ns typ, 1.89ns min, 476ps max; typ from 0 V to 0.557 V
|   rising waveform, R_fixture 50.000, V_fixture 1.200: 20-80 % time 369ps typ, 414ps min, 409ps max; typ from 0.393 V to 1.2 V
|   falling waveform, R_fixture 50.000, V_fixture 1.200: 20-80 % time 1.59ns typ, 3.17ns min, 579ps max; typ from 1.2 V to 0.393 V
|   falling waveform, R_fixture 50.000, V_fixture 0.0: 20-80 % time 397ps typ, 465ps min, 372ps max; typ from 0.557 V to 0 V
[Pulldown]
|Voltage   I(typ)   I(min)   I(max)
-1.2V     -47.32mA   -26.76mA   -74.29mA
-830mV    -47.32mA   -26.76mA   -73.83mA
-719mV    -46.75mA   -26.76mA   -70.83mA
-534mV    -39.41mA   -24.7mA    -62.22mA
-423mV    -32.02mA   -19.39mA   -52.05mA
95mV      5.729mA    2.992mA    10.49mA
354mV     15.29mA    7.674mA    28.14mA
761mV     19.19mA    9.392mA    35.13mA
1.649V    21.15mA    10.51mA    38.38mA
2.019V    25.42mA    15.26mA    39.86mA
2.167V    29.78mA    18.68mA    44.57mA
2.4V      38.6mA     25.26mA    56.96mA
[Pullup]
|Voltage   I(typ)   I(min)   I(max)
-1.2V     83.18mA    57.67mA    129.8mA
-893mV    59.32mA    41.68mA    92.9mA
-560mV    35.41mA    24.12mA    58.49mA
-338mV    19.19mA    13.06mA    32.47mA
-190mV    9.687mA    6.463mA    16.55mA
-79mV     3.668mA    2.398mA    6.116mA
32mV      -1.332mA   -852.4uA   -2.917mA
143mV     -5.255mA   -3.326mA   -10.26mA
254mV     -8.11mA    -5.063mA   -15.86mA
402mV     -10.32mA   -6.287mA   -20.71mA
587mV     -11.14mA   -6.66mA    -23.11mA
2.4V      -13.01mA   -7.654mA   -27.74mA
[GND_clamp]
|Voltage   I(typ)   I(min)   I(max)
-1.2V     -586.8mA   -561.7mA   -640.4mA
-1.075V   -375.3mA   -403.2mA   -342.9mA
-1V       -256.8mA   -312.4mA   -188.9mA
-950mV    -184.3mA   -254.5mA   -114.1mA
-925mV    -151.1mA   -226.6mA   -91.32mA
-875mV    -94.01mA   -173.6mA   -70.06mA
-800mV    -43.56mA   -102.9mA   -56.11mA
-725mV    -26.45mA   -48.06mA   -41.65mA
-650mV    -16.55mA   -16.39mA   -27.24mA
-575mV    -8.728mA   -5.059mA   -14.79mA
-375mV    -266.5uA   -129.3uA   -404.6uA
1.2V      0A         0A         0A
[POWER_clamp]
|Voltage   I(typ)   I(min)   I(max)
-1.2V     9.358mA    4.601mA    22.1mA
-950mV    6.537mA    3.101mA    16.64mA
-825mV    5.08mA     2.355mA    13.4mA
-775mV    4.466mA    2.06mA     11.6mA
-650mV    2.734mA    1.335mA    5.647mA
-600mV    1.907mA    1.053mA    3.642mA
-550mV    1.113mA    778.7uA    2.069mA
-525mV    798uA      647.5uA    1.472mA
-475mV    381.7uA    406uA      682.4uA
-425mV    196.4uA    214.2uA    354.3uA
-350mV    117.6uA    72.69uA    251.1uA
1.2V      0A         0A         29.9uA
[Ramp]
| variable   typ   min   max
dV/dt_r   0.334/1.023n   0.203/1.844n   0.557/0.473n
dV/dt_f   0.483/1.584n   0.277/3.163n   0.627/0.576n
R_load = 50.000
[Rising Waveform]
R_fixture= 50.000
V_fixture= 0.0
V_fixture_min= 0.0
V_fixture_max= 0.0
|time   V(typ)   V(min)   V(max)
0s        2.225nV    32.56nV    936.2pV
1.456ns   -111.2uV   6.268uV    -2.245mV
1.957ns   -5.92mV    31.17uV    594.2mV
2.21ns    -14.56mV   31.17uV    792.3mV
2.994ns   -6.824mV   -312.7uV   913.1mV
4.198ns   379.1mV    -8.799mV   926.5mV
5.237ns   515.2mV    -2.729mV   927.6mV
6.722ns   549.5mV    11.21mV    927.8mV
10.11ns   557.1mV    311.1mV    927.8mV
20ns      557.4mV    338.9mV    927.8mV
[Rising Waveform]
R_fixture= 50.000
V_fixture= 1.200
V_fixture_min= 1.140
V_fixture_max= 1.260
|time   V(typ)   V(min)   V(max)
0s        392.9mV    677.3mV    216.8mV
916ps     392.9mV    677.3mV    217.9mV
1.232ns   392.4mV    677.3mV    922.9mV
1.936ns   453.4mV    677.2mV    1.247V
2.163ns   872mV      676.6mV    1.255V
2.384ns   1.048V     676.5mV    1.259V
3.571ns   1.18V      658.8mV    1.262V
4.152ns   1.193V     1.03V      1.262V
4.736ns   1.197V     1.112V     1.262V
20ns      1.198V     1.139V     1.262V
[Falling Waveform]
R_fixture= 50.000
V_fixture= 1.200
V_fixture_min= 1.140
V_fixture_max= 1.260
|time   V(typ)   V(min)   V(max)
0s        1.198V     1.139V     1.262V
1.041ns   1.198V     1.139V     1.32V
1.537ns   1.199V     1.139V     1.24V
2.406ns   1.214V     1.139V     387mV
3.009ns   1.197V     1.14V      246.2mV
3.579ns   1.145V     1.138V     225.3mV
5.154ns   623.9mV    1.139V     217.3mV
6.84ns    429.5mV    1.131V     216.9mV
11.57ns   393.1mV    750mV      216.8mV
20ns      392.8mV    678.1mV    216.8mV
[Falling Waveform]
R_fixture= 50.000
V_fixture= 0.0
V_fixture_min= 0.0
V_fixture_max= 0.0
|time   V(typ)   V(min)   V(max)
0s        557.4mV    339mV      927.8mV
927ps     557.5mV    339.1mV    928.4mV
1.262ns   557.4mV    339.1mV    271.2mV
1.997ns   490.3mV    339mV      9.799mV
2.387ns   125.1mV    338.9mV    2.817mV
3.341ns   15.89mV    337mV      409.5uV
3.835ns   6.268mV    340.4mV    106.7uV
4.472ns   2.083mV    67.16mV    51.78uV
5.27ns    732.2uV    10.37mV    18.51uV
20ns      5.627nV    1.106uV    -4.891nV
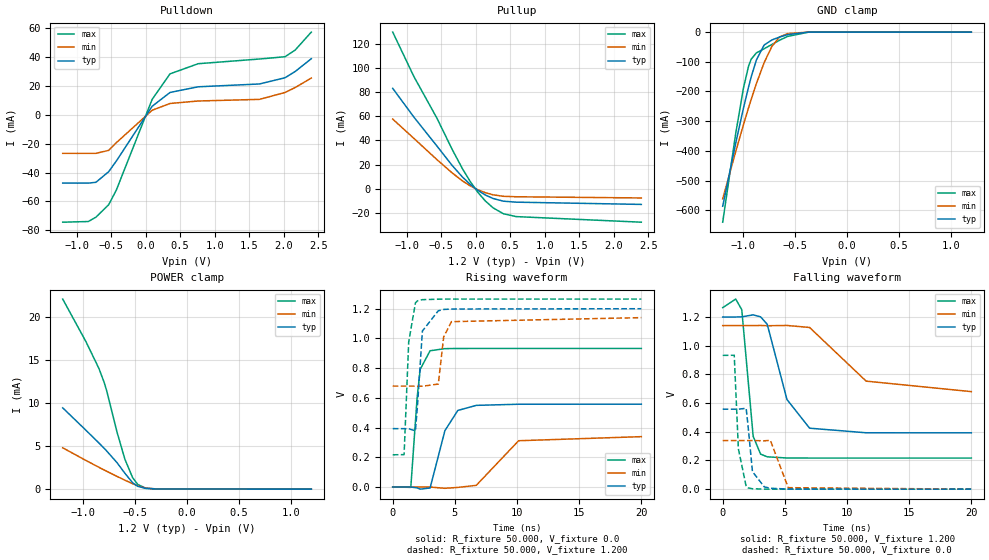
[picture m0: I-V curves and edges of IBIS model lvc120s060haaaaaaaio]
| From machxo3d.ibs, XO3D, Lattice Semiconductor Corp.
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|   Model lvc120s060haaaaaaaio
[Model] lvc120s060haaaaaaaio
Model_type I/O
Polarity   Non-Inverting
Enable   Active-Low
Vinl =  0.420V
Vinh =  0.780V
Vmeas =  0.600V
Cref =  0.0F
Rref =  1.000M
Vref =  0.0V
C_comp   4.200pF   3.800pF   7.500pF
[Temperature Range]   25.000   0.105k   -40.000
[Voltage Range]   1.200V   1.140V   1.260V
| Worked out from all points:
|   slope of the pulldown table from 0 to 0.18 V, typ, clamps not added: 18.4 ohm
|   slope of the pullup table from 0 to 0.18 V, typ, clamps not added: 28.4 ohm
|   GND clamp passes 1 mA (typ) near -0.44 V on its own axis
|   POWER clamp passes 1 mA (typ) near -0.55 V on its own axis
|   rising waveform, R_fixture 50.000, V_fixture 0.0: 20-80 % time 1.04ns typ, 1.89ns min, 482ps max; typ from 0 V to 0.557 V
|   rising waveform, R_fixture 50.000, V_fixture 1.200: 20-80 % time 372ps typ, 413ps min, 410ps max; typ from 0.393 V to 1.2 V
|   falling waveform, R_fixture 50.000, V_fixture 1.200: 20-80 % time 1.61ns typ, 3.2ns min, 585ps max; typ from 1.2 V to 0.393 V
|   falling waveform, R_fixture 50.000, V_fixture 0.0: 20-80 % time 396ps typ, 469ps min, 384ps max; typ from 0.557 V to 0 V
[Pulldown]
|Voltage   I(typ)   I(min)   I(max)
-1.2V     -47.32mA   -26.76mA   -74.29mA
-830mV    -47.32mA   -26.76mA   -73.83mA
-719mV    -46.75mA   -26.76mA   -70.83mA
-534mV    -39.41mA   -24.7mA    -62.22mA
-423mV    -32.02mA   -19.39mA   -52.05mA
95mV      5.729mA    2.992mA    10.49mA
354mV     15.29mA    7.674mA    28.14mA
761mV     19.19mA    9.392mA    35.13mA
1.649V    21.15mA    10.51mA    38.38mA
2.019V    25.43mA    15.27mA    39.95mA
2.167V    29.78mA    18.68mA    44.59mA
2.4V      38.6mA     25.27mA    56.97mA
[Pullup]
|Voltage   I(typ)   I(min)   I(max)
-1.2V     83.18mA    57.71mA    129.8mA
-893mV    59.32mA    41.68mA    92.93mA
-560mV    35.41mA    24.12mA    58.49mA
-338mV    19.19mA    13.06mA    32.47mA
-190mV    9.687mA    6.463mA    16.55mA
-79mV     3.668mA    2.398mA    6.116mA
32mV      -1.332mA   -852.4uA   -2.917mA
143mV     -5.255mA   -3.326mA   -10.26mA
254mV     -8.11mA    -5.063mA   -15.86mA
402mV     -10.32mA   -6.287mA   -20.71mA
587mV     -11.14mA   -6.66mA    -23.11mA
2.4V      -13.01mA   -7.654mA   -27.74mA
[GND_clamp]
|Voltage   I(typ)   I(min)   I(max)
-1.2V     -586.8mA   -561.7mA   -640.4mA
-1.075V   -375.3mA   -403.2mA   -342.9mA
-1V       -256.8mA   -312.4mA   -188.9mA
-950mV    -184.3mA   -254.5mA   -114.1mA
-925mV    -151.1mA   -226.6mA   -91.32mA
-875mV    -94.01mA   -173.6mA   -70.06mA
-800mV    -43.56mA   -102.9mA   -56.11mA
-725mV    -26.45mA   -48.06mA   -41.65mA
-650mV    -16.55mA   -16.39mA   -27.24mA
-575mV    -8.728mA   -5.059mA   -14.79mA
-375mV    -266.5uA   -129.3uA   -404.6uA
1.2V      -42.59nA   0A         -5.33uA
[POWER_clamp]
|Voltage   I(typ)   I(min)   I(max)
-1.2V     9.441mA    4.803mA    22.07mA
-975mV    6.83mA     3.329mA    17.11mA
-850mV    5.356mA    2.536mA    14mA
-800mV    4.744mA    2.228mA    12.4mA
-775mV    4.43mA     2.076mA    11.41mA
-675mV    3.065mA    1.478mA    6.596mA
-600mV    1.851mA    1.044mA    3.486mA
-525mV    744.7uA    632.6uA    1.337mA
-475mV    325.6uA    388.1uA    543.5uA
-400mV    86.39uA    124.7uA    120.1uA
-300mV    23.03uA    20.03uA    34.62uA
1.2V      0A         0A         0A
[Ramp]
| variable   typ   min   max
dV/dt_r   0.334/1.023n   0.203/1.844n   0.560/0.478n
dV/dt_f   0.484/1.587n   0.276/3.155n   0.629/0.579n
R_load = 50.000
[Rising Waveform]
R_fixture= 50.000
V_fixture= 0.0
V_fixture_min= 0.0
V_fixture_max= 0.0
|time   V(typ)   V(min)   V(max)
0s        2.225nV    32.56nV    936.2pV
1.456ns   -111.2uV   6.252uV    -2.245mV
1.957ns   -5.92mV    31.18uV    594.2mV
2.21ns    -14.56mV   31.18uV    792.3mV
3.008ns   -6.359mV   -312.7uV   917.1mV
4.198ns   379.1mV    -8.799mV   931.3mV
5.237ns   515.2mV    -2.728mV   932.4mV
6.722ns   549.5mV    11.21mV    932.6mV
10.13ns   557.1mV    311.5mV    932.6mV
20ns      557.4mV    338.9mV    932.6mV
[Rising Waveform]
R_fixture= 50.000
V_fixture= 1.200
V_fixture_min= 1.140
V_fixture_max= 1.260
|time   V(typ)   V(min)   V(max)
0s        392.9mV    679.1mV    216.8mV
916ps     392.9mV    679.2mV    217.9mV
1.286ns   392.4mV    679.1mV    975.3mV
1.827ns   378mV      678.9mV    1.239V
1.991ns   544.7mV    678.6mV    1.253V
2.389ns   1.05V      678.3mV    1.261V
3.667ns   1.186V     692.8mV    1.264V
4.102ns   1.195V     1.011V     1.265V
4.727ns   1.198V     1.113V     1.265V
20ns      1.2V       1.14V      1.265V
[Falling Waveform]
R_fixture= 50.000
V_fixture= 1.200
V_fixture_min= 1.140
V_fixture_max= 1.260
|time   V(typ)   V(min)   V(max)
0s        1.2V       1.14V      1.265V
1.045ns   1.2V       1.14V      1.325V
1.534ns   1.201V     1.14V      1.251V
2.45ns    1.215V     1.14V      368.6mV
3.049ns   1.201V     1.141V     244.2mV
3.583ns   1.149V     1.139V     225.5mV
5.167ns   625.2mV    1.141V     217.2mV
6.99ns    425mV      1.127V     216.8mV
11.54ns   393.1mV    752.9mV    216.8mV
20ns      392.7mV    679.9mV    216.8mV
[Falling Waveform]
R_fixture= 50.000
V_fixture= 0.0
V_fixture_min= 0.0
V_fixture_max= 0.0
|time   V(typ)   V(min)   V(max)
0s        557.4mV    339mV      932.6mV
927ps     557.5mV    339.1mV    933.4mV
1.262ns   557.4mV    339.1mV    280.9mV
1.886ns   563.8mV    339mV      18.76mV
2.026ns   452.4mV    339mV      8.904mV
2.393ns   122.7mV    338.9mV    2.859mV
3.341ns   15.89mV    337mV      418.8uV
3.835ns   6.282mV    340.4mV    111.2uV
5.27ns    739.1uV    10.37mV    20.02uV
20ns      5.627nV    1.106uV    -2.705nV
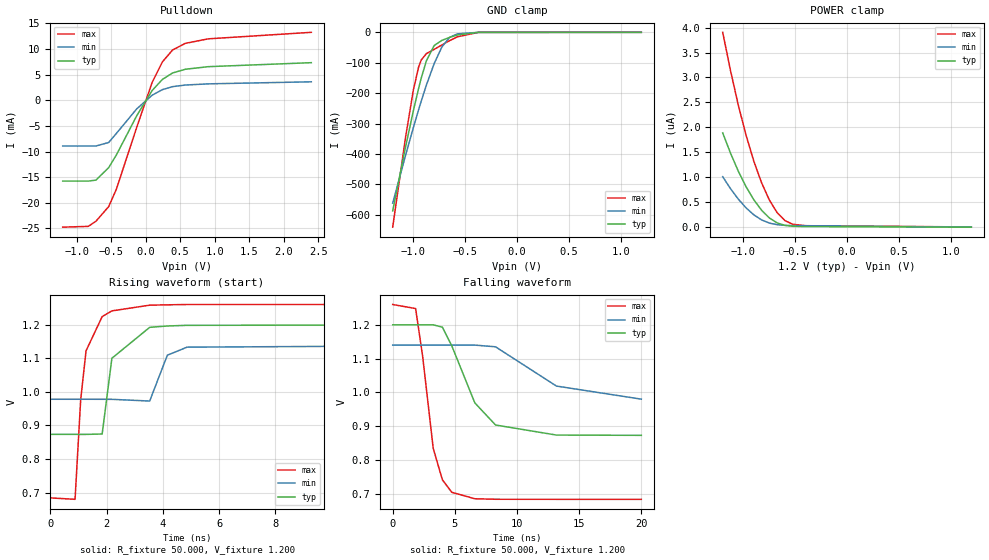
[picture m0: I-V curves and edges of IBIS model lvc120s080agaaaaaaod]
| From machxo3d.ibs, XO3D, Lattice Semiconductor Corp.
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|   Model lvc120s080agaaaaaaod
[Model] lvc120s080agaaaaaaod
Model_type I/O_open_drain
Polarity   Non-Inverting
Enable   Active-Low
Vinl =  0.420V
Vinh =  0.780V
Vmeas =  0.600V
Cref =  0.0F
Rref = 10.00k
Vref = 1.20V
C_comp   4.200pF   3.800pF   7.500pF
[Temperature Range]   25.000   0.105k   -40.000
[Voltage Range]   1.200V   1.140V   1.260V
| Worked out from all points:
|   slope of the pulldown table from 0 to 0.18 V, typ, clamps not added: 55.1 ohm
|   GND clamp passes 1 mA (typ) near -0.44 V on its own axis
|   rising waveform, R_fixture 50.000, V_fixture 1.200: 20-80 % time 362ps typ, 423ps min, 353ps max; typ from 0.873 V to 1.2 V
|   falling waveform, R_fixture 50.000, V_fixture 1.200: 20-80 % time 2.42ns typ, 4.18ns min, 1.25ns max; typ from 1.2 V to 0.873 V
[Pulldown]
|Voltage   I(typ)   I(min)   I(max)
-1.2V     -15.77mA   -8.921mA   -24.76mA
-830mV    -15.77mA   -8.921mA   -24.61mA
-719mV    -15.58mA   -8.921mA   -23.61mA
-534mV    -13.14mA   -8.234mA   -20.74mA
-423mV    -10.67mA   -6.463mA   -17.35mA
-127mV    -2.982mA   -1.659mA   -5.221mA
95mV      1.91mA     997.3uA    3.496mA
243mV     4.071mA    2.081mA    7.484mA
391mV     5.338mA    2.666mA    9.825mA
576mV     6.062mA    2.98mA     11.12mA
909mV     6.568mA    3.211mA    12mA
2.4V      7.346mA    3.612mA    13.27mA
[GND_clamp]
|Voltage   I(typ)   I(min)   I(max)
-1.2V     -586.8mA   -561.6mA   -640.4mA
-1.075V   -375.3mA   -403.2mA   -342.9mA
-1V       -256.8mA   -312.3mA   -188.8mA
-950mV    -184.3mA   -254.5mA   -114.1mA
-925mV    -151.1mA   -226.6mA   -91.28mA
-875mV    -93.98mA   -173.6mA   -70.02mA
-800mV    -43.52mA   -102.9mA   -56.06mA
-725mV    -26.41mA   -48.03mA   -41.59mA
-650mV    -16.51mA   -16.35mA   -27.18mA
-575mV    -8.675mA   -5.014mA   -14.71mA
-375mV    -184.4uA   -82.53uA   -274.8uA
1.2V      0A         0A         0A
[POWER_clamp]
|Voltage   I(typ)   I(min)   I(max)
-1.2V     1.889uA    1.011uA    3.905uA
-1.125V   1.485uA    772.5nA    3.141uA
-1.05V    1.124uA    563.1nA    2.451uA
-975mV    812.1nA    387.4nA    1.845uA
-900mV    550nA      247.6nA    1.324uA
-825mV    340.1nA    145.7nA    890.5nA
-750mV    184.8nA    81.66nA    545.5nA
-675mV    85.55nA    49.13nA    292.1nA
-600mV    35.84nA    36.01nA    132.7nA
-525mV    17.83nA    31.31nA    57.75nA
-400mV    11.62nA    28.65nA    28.91nA
1.2V      0A         0A         3.813nA
[Ramp]
| variable   typ   min   max
dV/dt_r   0.196/0.363n   97.283m/0.417n   0.346/0.349n
dV/dt_f   0.196/2.423n   95.813m/4.046n   0.346/1.252n
R_load = 50.000
[Rising Waveform]
R_fixture= 50.000
V_fixture= 1.200
V_fixture_min= 1.140
V_fixture_max= 1.260
|time   V(typ)   V(min)   V(max)
0s        873.4mV    977.9mV    684.3mV
881ps     873.4mV    977.9mV    680mV
1.08ns    873.3mV    977.9mV    975.5mV
1.271ns   873.3mV    977.9mV    1.122V
1.844ns   874.5mV    977.8mV    1.224V
2.19ns    1.1V       977.7mV    1.241V
3.533ns   1.192V     972.6mV    1.258V
4.16ns    1.196V     1.109V     1.259V
4.86ns    1.198V     1.133V     1.26V
20ns      1.2V       1.14V      1.26V
[Falling Waveform]
R_fixture= 50.000
V_fixture= 1.200
V_fixture_min= 1.140
V_fixture_max= 1.260
|time   V(typ)   V(min)   V(max)
0s        1.2V       1.14V      1.26V
1.842ns   1.2V       1.14V      1.248V
2.405ns   1.2V       1.14V      1.108V
3.26ns    1.2V       1.14V      834.7mV
3.996ns   1.193V     1.14V      742.1mV
4.751ns   1.138V     1.14V      705.1mV
6.607ns   969.2mV    1.14V      686mV
8.272ns   904mV      1.135V     684.5mV
13.17ns   874.2mV    1.019V     684.3mV
20ns      873.4mV    980.3mV    684.3mV
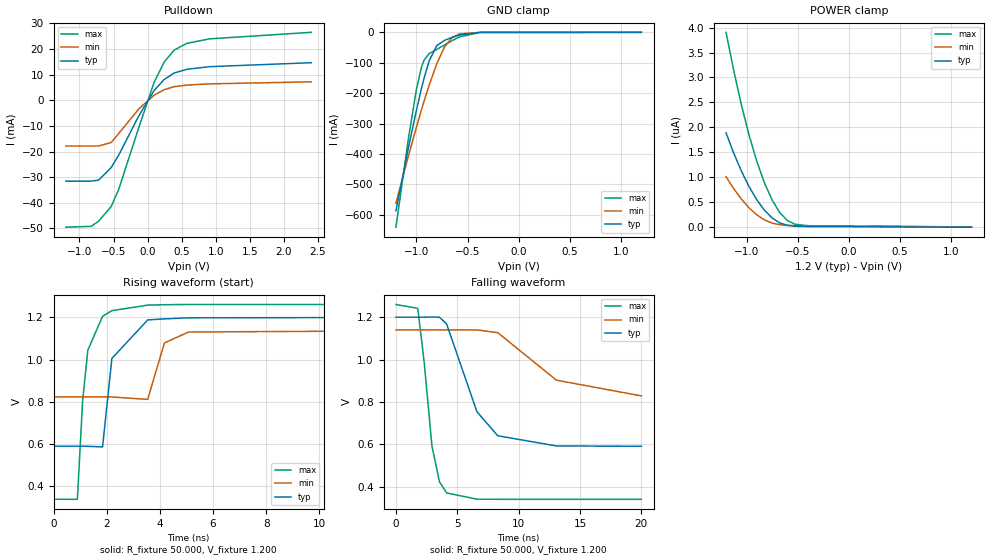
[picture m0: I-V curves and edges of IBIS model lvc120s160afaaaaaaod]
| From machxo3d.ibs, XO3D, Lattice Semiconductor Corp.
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|   Model lvc120s160afaaaaaaod
[Model] lvc120s160afaaaaaaod
Model_type I/O_open_drain
Polarity   Non-Inverting
Enable   Active-Low
Vinl =  0.420V
Vinh =  0.780V
Vmeas =  0.600V
Cref =  0.0F
Rref = 10.00k
Vref = 1.20V
C_comp   4.200pF   3.800pF   7.500pF
[Temperature Range]   25.000   0.105k   -40.000
[Voltage Range]   1.200V   1.140V   1.260V
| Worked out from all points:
|   slope of the pulldown table from 0 to 0.18 V, typ, clamps not added: 27.5 ohm
|   GND clamp passes 1 mA (typ) near -0.44 V on its own axis
|   rising waveform, R_fixture 50.000, V_fixture 1.200: 20-80 % time 364ps typ, 412ps min, 347ps max; typ from 0.59 V to 1.2 V
|   falling waveform, R_fixture 50.000, V_fixture 1.200: 20-80 % time 2.38ns typ, 4.15ns min, 987ps max; typ from 1.2 V to 0.59 V
[Pulldown]
|Voltage   I(typ)   I(min)   I(max)
-1.2V     -31.54mA   -17.84mA   -49.52mA
-830mV    -31.54mA   -17.84mA   -49.22mA
-719mV    -31.17mA   -17.84mA   -47.22mA
-534mV    -26.27mA   -16.47mA   -41.48mA
-423mV    -21.34mA   -12.93mA   -34.7mA
-127mV    -5.964mA   -3.318mA   -10.44mA
95mV      3.82mA     1.995mA    6.992mA
243mV     8.142mA    4.162mA    14.97mA
391mV     10.68mA    5.332mA    19.65mA
576mV     12.12mA    5.96mA     22.25mA
909mV     13.14mA    6.423mA    24mA
2.4V      14.69mA    7.225mA    26.55mA
[GND_clamp]
|Voltage   I(typ)   I(min)   I(max)
-1.2V     -586.8mA   -561.6mA   -640.4mA
-1.075V   -375.3mA   -403.2mA   -342.9mA
-1V       -256.8mA   -312.3mA   -188.8mA
-950mV    -184.3mA   -254.5mA   -114.1mA
-925mV    -151.1mA   -226.6mA   -91.28mA
-875mV    -93.98mA   -173.6mA   -70.02mA
-800mV    -43.52mA   -102.9mA   -56.06mA
-725mV    -26.41mA   -48.03mA   -41.59mA
-650mV    -16.51mA   -16.35mA   -27.18mA
-575mV    -8.675mA   -5.014mA   -14.71mA
-375mV    -184.4uA   -82.53uA   -274.8uA
1.2V      0A         0A         0A
[POWER_clamp]
|Voltage   I(typ)   I(min)   I(max)
-1.2V     1.889uA    1.011uA    3.905uA
-1.125V   1.485uA    772.5nA    3.141uA
-1.05V    1.124uA    563.1nA    2.451uA
-975mV    812.1nA    387.4nA    1.845uA
-900mV    550.1nA    247.6nA    1.324uA
-825mV    340.1nA    145.7nA    890.5nA
-750mV    184.9nA    81.65nA    545.5nA
-675mV    85.57nA    49.12nA    292.2nA
-600mV    35.85nA    36nA       132.8nA
-525mV    17.84nA    31.3nA     57.78nA
-400mV    11.63nA    28.64nA    28.94nA
1.2V      0A         0A         3.813nA
[Ramp]
| variable   typ   min   max
dV/dt_r   0.366/0.358n   0.190/0.420n   0.554/0.348n
dV/dt_f   0.366/2.381n   0.187/4.044n   0.554/0.996n
R_load = 50.000
[Rising Waveform]
R_fixture= 50.000
V_fixture= 1.200
V_fixture_min= 1.140
V_fixture_max= 1.260
|time   V(typ)   V(min)   V(max)
0s        590.1mV    823.2mV    339.5mV
897ps     590.1mV    823.2mV    339mV
1.096ns   590mV      823.2mV    808mV
1.29ns    589.6mV    823.2mV    1.044V
1.844ns   586.7mV    823.1mV    1.204V
2.195ns   1.005V     822.8mV    1.231V
3.541ns   1.187V     811.4mV    1.257V
4.17ns    1.192V     1.078V     1.259V
5.077ns   1.197V     1.13V      1.26V
20ns      1.2V       1.14V      1.26V
[Falling Waveform]
R_fixture= 50.000
V_fixture= 1.200
V_fixture_min= 1.140
V_fixture_max= 1.260
|time   V(typ)   V(min)   V(max)
0s        1.2V       1.14V      1.26V
1.781ns   1.2V       1.14V      1.242V
2.298ns   1.2V       1.14V      989.8mV
2.937ns   1.201V     1.14V      590.8mV
3.548ns   1.2V       1.14V      422.5mV
4.13ns    1.168V     1.14V      369.6mV
6.601ns   753.4mV    1.14V      340.2mV
8.295ns   639.8mV    1.127V     339.5mV
13.08ns   591.6mV    902.4mV    339.4mV
20ns      590.1mV    828.1mV    339.4mV
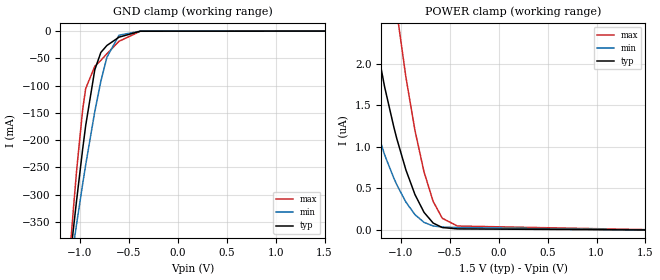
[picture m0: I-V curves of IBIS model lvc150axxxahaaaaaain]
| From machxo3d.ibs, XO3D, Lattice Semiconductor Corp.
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|   Model lvc150axxxahaaaaaain
[Model] lvc150axxxahaaaaaain
Model_type Input
Polarity   Non-Inverting
Enable   Active-High
Vinl =  0.375V
Vinh =  1.125V
C_comp   4.200pF   3.800pF   7.500pF
[Temperature Range]   25.000   0.105k   -40.000
[Voltage Range]   1.500V   1.430V   1.580V
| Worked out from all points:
|   GND clamp passes 1 mA (typ) near -0.44 V on its own axis
[GND_clamp]
|Voltage   I(typ)   I(min)   I(max)
-1.5V     -1.124A    -960.6mA   -1.411A
-1.097V   -411.6mA   -430.5mA   -392.9mA
-1.066V   -360.7mA   -392.1mA   -323mA
-1.035V   -311mA     -354.2mA   -256.7mA
-973mV    -216.8mA   -280.8mA   -144.2mA
-942mV    -173.4mA   -245.5mA   -105.6mA
-849mV    -71.05mA   -147.7mA   -64.59mA
-787mV    -39.16mA   -92.07mA   -53.68mA
-725mV    -26.4mA    -48.02mA   -41.58mA
-601mV    -11.15mA   -7.544mA   -18.72mA
-384mV    -236.4uA   -103.3uA   -351.1uA
1.5V      0A         0A         0A
[POWER_clamp]
|Voltage   I(typ)   I(min)   I(max)
-1.5V     4.017uA    2.297uA    8.486uA
-1.321V   2.676uA    1.475uA    5.815uA
-1.166V   1.719uA    902.9nA    3.892uA
-1.073V   1.242uA    625.4nA    2.92uA
-1.042V   1.099uA    544.2nA    2.626uA
-949mV    723.1nA    335.9nA    1.84uA
-856mV    425.6nA    184nA      1.196uA
-763mV    211.1nA    90.97nA    695.6nA
-670mV    83.04nA    48.45nA    343.1nA
-577mV    29.39nA    34.64nA    141nA
-422mV    12.83nA    29.53nA    47.29nA
1.5V      0A         0A         4.131nA
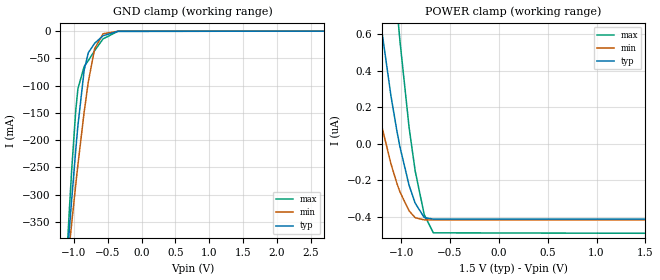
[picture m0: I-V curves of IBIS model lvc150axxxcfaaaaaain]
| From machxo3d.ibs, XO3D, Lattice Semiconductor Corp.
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|   Model lvc150axxxcfaaaaaain
[Model] lvc150axxxcfaaaaaain
Model_type Input
Polarity   Non-Inverting
Enable   Active-High
Vinl =  0.375V
Vinh =  1.125V
C_comp   4.200pF   3.800pF   7.500pF
[Temperature Range]   25.000   0.105k   -40.000
[Voltage Range]   1.500V   1.430V   1.580V
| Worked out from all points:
|   GND clamp passes 1 mA (typ) near -0.43 V on its own axis
[GND_clamp]
|Voltage   I(typ)   I(min)   I(max)
-1.5V     -1.124A    -960.6mA   -1.411A
-1.097V   -411.6mA   -430.5mA   -393mA
-1.066V   -360.7mA   -392.1mA   -323mA
-1.035V   -311mA     -354.2mA   -256.8mA
-973mV    -216.9mA   -280.8mA   -144.3mA
-942mV    -173.5mA   -245.5mA   -105.7mA
-849mV    -71.09mA   -147.7mA   -64.66mA
-787mV    -39.21mA   -92.09mA   -53.75mA
-694mV    -22.05mA   -31.84mA   -35.55mA
-570mV    -8.285mA   -4.678mA   -14.06mA
-353mV    -178.3uA   -91.12uA   -279.1uA
3V        108.1uA    41.24uA    254.4uA
[POWER_clamp]
|Voltage   I(typ)   I(min)   I(max)
-1.5V     2.264uA    1.09uA     5.325uA
-1.383V   1.543uA    646.9nA    3.832uA
-1.29V    1.045uA    348.8nA    2.802uA
-1.197V   619.1nA    96.03nA    1.914uA
-1.104V   264.3nA    -108.5nA   1.168uA
-1.042V   67.86nA    -217.5nA   747.1nA
-1.011V   -18.2nA    -263.5nA   559.8nA
-918mV    -227nA     -366.2nA   89.62nA
-856mV    -324nA     -403.7nA   -147.4nA
-763mV    -403.1nA   -415.8nA   -387.4nA
-670mV    -411.5nA   -415.8nA   -486.7nA
1.5V      -411.5nA   -415.8nA   -489.1nA
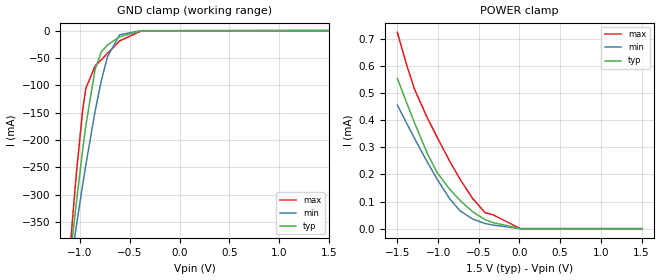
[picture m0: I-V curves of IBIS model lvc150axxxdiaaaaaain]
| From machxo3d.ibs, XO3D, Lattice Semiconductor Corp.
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|   Model lvc150axxxdiaaaaaain
[Model] lvc150axxxdiaaaaaain
Model_type Input
Polarity   Non-Inverting
Enable   Active-High
Vinl =  0.375V
Vinh =  1.125V
C_comp   4.200pF   3.800pF   7.500pF
[Temperature Range]   25.000   0.105k   -40.000
[Voltage Range]   1.500V   1.430V   1.580V
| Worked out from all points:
|   GND clamp passes 1 mA (typ) near -0.43 V on its own axis
[GND_clamp]
|Voltage   I(typ)   I(min)   I(max)
-1.5V     -1.124A    -960.6mA   -1.411A
-1.097V   -411.6mA   -430.5mA   -393mA
-1.066V   -360.7mA   -392.1mA   -323mA
-1.035V   -311mA     -354.2mA   -256.8mA
-973mV    -216.9mA   -280.8mA   -144.3mA
-942mV    -173.5mA   -245.5mA   -105.7mA
-849mV    -71.09mA   -147.7mA   -64.66mA
-787mV    -39.21mA   -92.09mA   -53.75mA
-725mV    -26.45mA   -48.04mA   -41.65mA
-601mV    -11.21mA   -7.588mA   -18.81mA
-384mV    -319.8uA   -151.2uA   -484.4uA
1.5V      -41.68nA   0A         -8.283uA
[POWER_clamp]
|Voltage   I(typ)   I(min)   I(max)
-1.5V     553.8uA    455.7uA    723.9uA
-1.383V   462uA      386.8uA    600.3uA
-1.29V    390.6uA    333.2uA    514.8uA
-1.135V   279.1uA    247uA      410.2uA
-1.011V   206.7uA    182uA      336.5uA
-856mV    145uA      109.7uA    248.3uA
-732mV    104.8uA    66.29uA    183.2uA
-577mV    62.52uA    35.6uA     111.7uA
-422mV    33.03uA    19.13uA    58.98uA
-329mV    22.6uA     13.31uA    51.73uA
12mV      0A         0A         0A
1.5V      0A         0A         0A
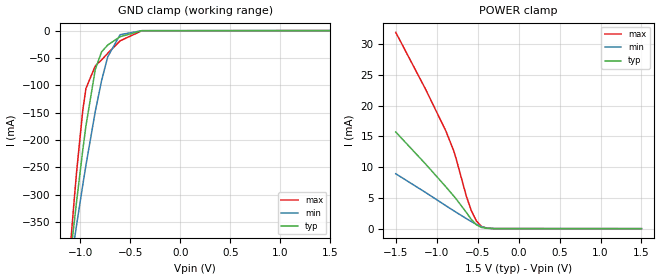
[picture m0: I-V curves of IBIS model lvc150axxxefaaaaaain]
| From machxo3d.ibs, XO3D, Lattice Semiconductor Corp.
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|   Model lvc150axxxefaaaaaain
[Model] lvc150axxxefaaaaaain
Model_type Input
Polarity   Non-Inverting
Enable   Active-High
Vinl =  0.375V
Vinh =  1.125V
C_comp   4.200pF   3.800pF   7.500pF
[Temperature Range]   25.000   0.105k   -40.000
[Voltage Range]   1.500V   1.430V   1.580V
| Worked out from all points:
|   GND clamp passes 1 mA (typ) near -0.44 V on its own axis
|   POWER clamp passes 1 mA (typ) near -0.55 V on its own axis
[GND_clamp]
|Voltage   I(typ)   I(min)   I(max)
-1.5V     -1.124A    -960.6mA   -1.411A
-1.097V   -411.6mA   -430.5mA   -392.9mA
-1.066V   -360.7mA   -392.1mA   -323mA
-1.035V   -311mA     -354.2mA   -256.7mA
-973mV    -216.8mA   -280.8mA   -144.2mA
-942mV    -173.4mA   -245.5mA   -105.6mA
-849mV    -71.05mA   -147.7mA   -64.59mA
-787mV    -39.16mA   -92.07mA   -53.68mA
-725mV    -26.4mA    -48.02mA   -41.58mA
-601mV    -11.15mA   -7.544mA   -18.72mA
-384mV    -236.4uA   -103.3uA   -351.1uA
1.5V      0A         0A         0A
[POWER_clamp]
|Voltage   I(typ)   I(min)   I(max)
-1.5V     15.72mA    8.929mA    31.93mA
-1.135V   10.5mA     5.879mA    22.65mA
-887mV    6.787mA    3.722mA    15.85mA
-794mV    5.333mA    2.928mA    12.72mA
-763mV    4.831mA    2.666mA    11.38mA
-639mV    2.654mA    1.642mA    5.303mA
-577mV    1.493mA    1.154mA    2.909mA
-515mV    627.3uA    700.9uA    1.235mA
-453mV    200.7uA    325.5uA    363.9uA
-391mV    56.19uA    99.29uA    82.51uA
-298mV    7.73uA     11.12uA    7.668uA
1.5V      0A         0A         4.131nA
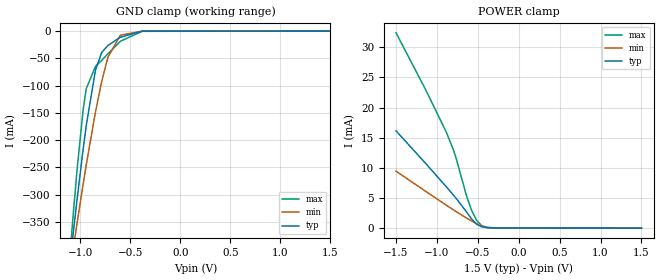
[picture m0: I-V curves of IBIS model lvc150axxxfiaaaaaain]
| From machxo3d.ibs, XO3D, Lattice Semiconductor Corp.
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|   Model lvc150axxxfiaaaaaain
[Model] lvc150axxxfiaaaaaain
Model_type Input
Polarity   Non-Inverting
Enable   Active-High
Vinl =  0.375V
Vinh =  1.125V
C_comp   4.200pF   3.800pF   7.500pF
[Temperature Range]   25.000   0.105k   -40.000
[Voltage Range]   1.500V   1.430V   1.580V
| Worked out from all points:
|   GND clamp passes 1 mA (typ) near -0.44 V on its own axis
|   POWER clamp passes 1 mA (typ) near -0.54 V on its own axis
[GND_clamp]
|Voltage   I(typ)   I(min)   I(max)
-1.5V     -1.124A    -960.6mA   -1.411A
-1.097V   -411.6mA   -430.5mA   -392.9mA
-1.066V   -360.7mA   -392.1mA   -323mA
-1.035V   -311mA     -354.2mA   -256.7mA
-973mV    -216.8mA   -280.8mA   -144.3mA
-942mV    -173.5mA   -245.5mA   -105.7mA
-849mV    -71.06mA   -147.7mA   -64.61mA
-787mV    -39.17mA   -92.07mA   -53.7mA
-725mV    -26.41mA   -48.02mA   -41.6mA
-601mV    -11.16mA   -7.552mA   -18.74mA
-384mV    -258.6uA   -114.9uA   -396.2uA
1.5V      -41.68nA   0A         -8.283uA
[POWER_clamp]
|Voltage   I(typ)   I(min)   I(max)
-1.5V     16.13mA    9.435mA    32.38mA
-1.135V   10.69mA    6.084mA    22.87mA
-887mV    6.888mA    3.813mA    15.95mA
-794mV    5.406mA    2.992mA    12.8mA
-763mV    4.897mA    2.724mA    11.46mA
-639mV    2.697mA    1.677mA    5.367mA
-577mV    1.529mA    1.181mA    2.962mA
-515mV    656.7uA    722.8uA    1.279mA
-453mV    227.4uA    343.3uA    403.8uA
-391mV    80.76uA    114.4uA    122.7uA
-267mV    21.1uA     15.5uA     34.42uA
1.5V      0A         0A         0A
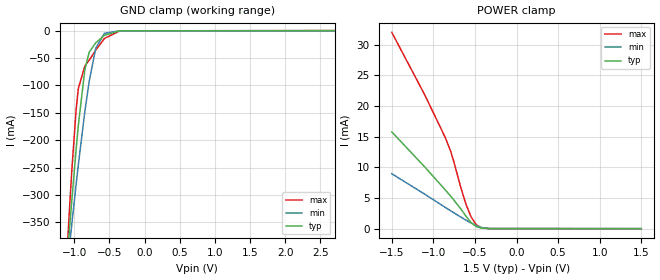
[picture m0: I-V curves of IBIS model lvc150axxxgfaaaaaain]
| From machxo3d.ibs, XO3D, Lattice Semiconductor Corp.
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|   Model lvc150axxxgfaaaaaain
[Model] lvc150axxxgfaaaaaain
Model_type Input
Polarity   Non-Inverting
Enable   Active-High
Vinl =  0.375V
Vinh =  1.125V
C_comp   4.200pF   3.800pF   7.500pF
[Temperature Range]   25.000   0.105k   -40.000
[Voltage Range]   1.500V   1.430V   1.580V
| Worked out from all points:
|   GND clamp passes 1 mA (typ) near -0.43 V on its own axis
|   POWER clamp passes 1 mA (typ) near -0.55 V on its own axis
[GND_clamp]
|Voltage   I(typ)   I(min)   I(max)
-1.5V     -1.124A    -960.6mA   -1.411A
-1.097V   -411.6mA   -430.5mA   -393mA
-1.066V   -360.7mA   -392.1mA   -323mA
-1.035V   -311mA     -354.2mA   -256.8mA
-973mV    -216.9mA   -280.8mA   -144.3mA
-942mV    -173.5mA   -245.5mA   -105.7mA
-849mV    -71.09mA   -147.7mA   -64.66mA
-787mV    -39.21mA   -92.09mA   -53.75mA
-694mV    -22.05mA   -31.84mA   -35.55mA
-570mV    -8.285mA   -4.678mA   -14.06mA
-353mV    -178.3uA   -91.12uA   -279.1uA
3V        108.1uA    41.24uA    254.4uA
[POWER_clamp]
|Voltage   I(typ)   I(min)   I(max)
-1.5V     15.78mA    8.958mA    32.02mA
-1.104V   10.07mA    5.622mA    21.83mA
-856mV    6.305mA    3.46mA     14.84mA
-794mV    5.324mA    2.93mA     12.69mA
-763mV    4.82mA     2.667mA    11.36mA
-670mV    3.216mA    1.891mA    6.697mA
-608mV    2.042mA    1.391mA    3.973mA
-546mV    979.4uA    916.1uA    1.9mA
-484mV    340.1uA    494.4uA    627.5uA
-422mV    90.48uA    185.7uA    125.7uA
-329mV    10.53uA    21.57uA    6.907uA
1.5V      0A         0A         -3.95nA
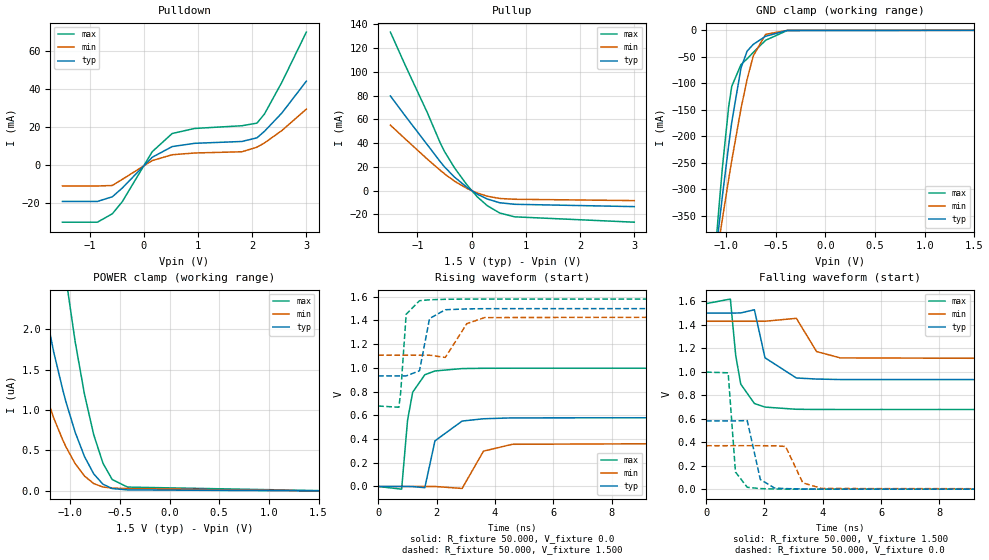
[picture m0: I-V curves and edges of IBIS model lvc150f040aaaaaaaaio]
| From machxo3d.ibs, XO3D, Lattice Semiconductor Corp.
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|   Model lvc150f040aaaaaaaaio
[Model] lvc150f040aaaaaaaaio
Model_type I/O
Polarity   Non-Inverting
Enable   Active-Low
Vinl =  0.375V
Vinh =  1.125V
Vmeas =  0.750V
Cref =  0.0F
Rref =  1.000M
Vref =  0.0V
C_comp   4.200pF   3.800pF   7.500pF
[Temperature Range]   25.000   0.105k   -40.000
[Voltage Range]   1.500V   1.430V   1.580V
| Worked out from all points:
|   slope of the pulldown table from 0 to 0.225 V, typ, clamps not added: 40.7 ohm
|   slope of the pullup table from 0 to 0.225 V, typ, clamps not added: 38.9 ohm
|   GND clamp passes 1 mA (typ) near -0.44 V on its own axis
|   rising waveform, R_fixture 50.000, V_fixture 0.0: 20-80 % time 418ps typ, 496ps min, 298ps max; typ from 0 V to 0.581 V
|   rising waveform, R_fixture 50.000, V_fixture 1.500: 20-80 % time 260ps typ, 435ps min, 140ps max; typ from 0.932 V to 1.5 V
|   falling waveform, R_fixture 50.000, V_fixture 1.500: 20-80 % time 377ps typ, 483ps min, 314ps max; typ from 1.5 V to 0.932 V
|   falling waveform, R_fixture 50.000, V_fixture 0.0: 20-80 % time 249ps typ, 395ps min, 149ps max; typ from 0.581 V to 0 V
[Pulldown]
|Voltage   I(typ)   I(min)   I(max)
-1.5V     -19.1mA    -10.99mA   -29.96mA
-856mV    -19.1mA    -10.99mA   -29.96mA
-580mV    -16.64mA   -10.73mA   -25.56mA
-396mV    -12.04mA   -7.496mA   -19.19mA
156mV     4.064mA    2.312mA    6.984mA
524mV     9.661mA    5.388mA    16.51mA
938mV     11.37mA    6.303mA    19.16mA
1.812V    12.34mA    6.944mA    20.58mA
2.088V    14.25mA    9.352mA    21.95mA
2.226V    17.63mA    11.53mA    26.68mA
2.548V    27.25mA    18.06mA    43.35mA
3V        43.93mA    29.29mA    69.66mA
[Pullup]
|Voltage   I(typ)   I(min)   I(max)
-1.5V     79.77mA    55.2mA     133.5mA
-1.232V   63.31mA    43.8mA     106.2mA
-818mV    38.64mA    26.54mA    65.65mA
-588mV    24.9mA     17.48mA    41mA
-496mV    19.72mA    14.01mA    32.57mA
-312mV    11.25mA    7.838mA    18.9mA
-82mV     2.627mA    1.78mA     4.548mA
102mV     -2.891mA   -1.927mA   -5.109mA
286mV     -6.99mA    -4.605mA   -12.56mA
516mV     -10.15mA   -6.555mA   -18.77mA
792mV     -11.45mA   -7.225mA   -22.01mA
3V        -13.42mA   -8.343mA   -26.52mA
[GND_clamp]
|Voltage   I(typ)   I(min)   I(max)
-1.5V     -1.124A    -960.6mA   -1.411A
-1.097V   -411.6mA   -430.5mA   -392.9mA
-1.066V   -360.7mA   -392.1mA   -323mA
-1.035V   -311mA     -354.2mA   -256.7mA
-973mV    -216.8mA   -280.8mA   -144.2mA
-942mV    -173.4mA   -245.5mA   -105.6mA
-849mV    -71.05mA   -147.7mA   -64.59mA
-787mV    -39.16mA   -92.07mA   -53.68mA
-725mV    -26.4mA    -48.02mA   -41.58mA
-601mV    -11.15mA   -7.544mA   -18.72mA
-384mV    -236.4uA   -103.3uA   -351.1uA
1.5V      0A         0A         0A
[POWER_clamp]
|Voltage   I(typ)   I(min)   I(max)
-1.5V     4.017uA    2.297uA    8.486uA
-1.321V   2.676uA    1.475uA    5.815uA
-1.166V   1.719uA    902.9nA    3.892uA
-1.073V   1.242uA    625.4nA    2.92uA
-1.042V   1.099uA    544.2nA    2.626uA
-949mV    723.1nA    335.9nA    1.84uA
-856mV    425.6nA    184nA      1.196uA
-763mV    211.1nA    90.94nA    695.6nA
-670mV    83.04nA    48.42nA    343.1nA
-577mV    29.39nA    34.61nA    141nA
-422mV    12.83nA    29.5nA     47.29nA
1.5V      0A         0A         4.131nA
[Ramp]
| variable   typ   min   max
dV/dt_r   0.349/0.408n   0.222/0.495n   0.598/0.299n
dV/dt_f   0.341/0.380n   0.194/0.491n   0.541/0.315n
R_load = 50.000
[Rising Waveform]
R_fixture= 50.000
V_fixture= 0.0
V_fixture_min= 0.0
V_fixture_max= 0.0
|time   V(typ)   V(min)   V(max)
0s        4.722nV    51.53nV    2.531nV
803ps     24.62uV    32.21uV    -22.65mV
1.006ns   180.6uV    7.232uV    557.2mV
1.182ns   -750.5uV   7.232uV    794.7mV
1.598ns   -10.39mV   97.69uV    941.8mV
1.946ns   384.7mV    92.19uV    973.8mV
2.876ns   551.5mV    -16.66mV   994mV
3.61ns    570.9mV    298mV      996.5mV
4.598ns   578.4mV    355.7mV    997mV
20ns      581.2mV    370.1mV    997.2mV
[Rising Waveform]
R_fixture= 50.000
V_fixture= 1.500
V_fixture_min= 1.430
V_fixture_max= 1.580
|time   V(typ)   V(min)   V(max)
0s        932.1mV    1.107V     678.4mV
707ps     932.1mV    1.107V     668.1mV
772ps     932mV      1.107V     794mV
959ps     932.4mV    1.107V     1.452V
1.416ns   975.6mV    1.107V     1.566V
1.761ns   1.416V     1.107V     1.574V
2.3ns     1.49V      1.088V     1.578V
3.039ns   1.497V     1.373V     1.58V
3.647ns   1.499V     1.424V     1.58V
20ns      1.5V       1.43V      1.58V
[Falling Waveform]
R_fixture= 50.000
V_fixture= 1.500
V_fixture_min= 1.430
V_fixture_max= 1.580
|time   V(typ)   V(min)   V(max)
0s        1.5V       1.43V      1.58V
832ps     1.5V       1.43V      1.619V
1.016ns   1.5V       1.43V      1.137V
1.188ns   1.501V     1.43V      894.6mV
1.656ns   1.528V     1.43V      729.6mV
2.019ns   1.119V     1.43V      699mV
3.096ns   946.9mV    1.455V     680.4mV
3.789ns   937.7mV    1.172V     678.8mV
4.6ns     933.7mV    1.118V     678.5mV
20ns      932.1mV    1.107V     678.4mV
[Falling Waveform]
R_fixture= 50.000
V_fixture= 0.0
V_fixture_min= 0.0
V_fixture_max= 0.0
|time   V(typ)   V(min)   V(max)
0s        581.2mV    370.1mV    997.2mV
756ps     581.3mV    370mV      990.8mV
1.007ns   581.3mV    370.2mV    146.1mV
1.41ns    584.3mV    370.1mV    16.06mV
1.86ns    82.34mV    370.1mV    4.92mV
2.344ns   9.921mV    369.5mV    1.276mV
2.725ns   4.587mV    364mV      488.2uV
3.316ns   1.707mV    53.46mV    153.7uV
3.974ns   590.3uV    5.733mV    43.77uV
20ns      -110.5nV   45.57nV    -214.2nV
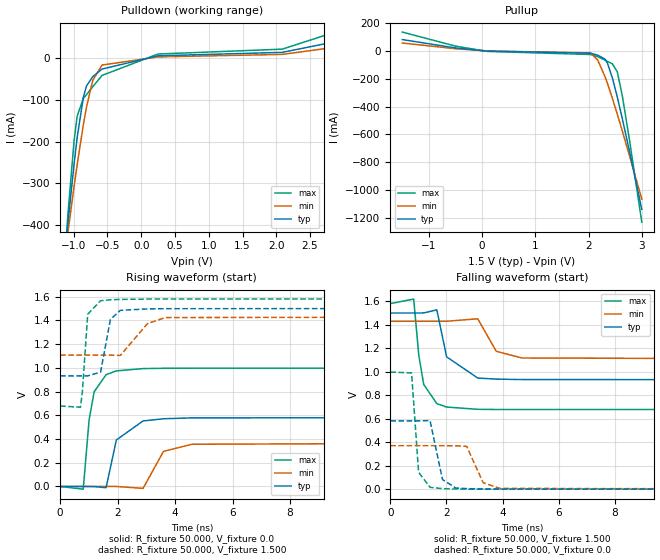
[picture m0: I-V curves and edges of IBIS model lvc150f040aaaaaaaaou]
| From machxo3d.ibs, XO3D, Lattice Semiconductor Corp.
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|   Model lvc150f040aaaaaaaaou
[Model] lvc150f040aaaaaaaaou
Model_type Output
Polarity   Non-Inverting
Enable   Active-High
Vmeas =  0.750V
Cref =  0.0F
Rref =  1.000M
Vref =  0.0V
C_comp   4.200pF   3.800pF   7.500pF
[Temperature Range]   25.000   0.105k   -40.000
[Voltage Range]   1.500V   1.430V   1.580V
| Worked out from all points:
|   slope of the pulldown table from 0 to 0.225 V, typ, clamps not added: 40.7 ohm
|   slope of the pullup table from 0 to 0.225 V, typ, clamps not added: 38.9 ohm
|   rising waveform, R_fixture 50.000, V_fixture 0.0: 20-80 % time 419ps typ, 491ps min, 296ps max; typ from 0 V to 0.581 V
|   rising waveform, R_fixture 50.000, V_fixture 1.500: 20-80 % time 260ps typ, 434ps min, 139ps max; typ from 0.932 V to 1.5 V
|   falling waveform, R_fixture 50.000, V_fixture 1.500: 20-80 % time 378ps typ, 450ps min, 313ps max; typ from 1.5 V to 0.932 V
|   falling waveform, R_fixture 50.000, V_fixture 0.0: 20-80 % time 248ps typ, 400ps min, 148ps max; typ from 0.581 V to 0 V
[Pulldown]
|Voltage   I(typ)   I(min)   I(max)
-1.5V     -1.125A    -961.3mA   -1.413A
-1.132V   -473mA     -476mA     -480.5mA
-1.086V   -396.8mA   -418.5mA   -375.7mA
-994mV    -253.7mA   -307.5mA   -198.1mA
-948mV    -190mA     -254.9mA   -138.6mA
-856mV    -93.02mA   -158.7mA   -95.89mA
-810mV    -66.23mA   -117mA     -87.24mA
-718mV    -44.12mA   -53.14mA   -68.34mA
-580mV    -25.78mA   -16.15mA   -41.02mA
248mV     5.973mA    3.382mA    10.27mA
2.088V    14.25mA    9.352mA    21.95mA
3V        43.94mA    29.29mA    69.67mA
[Pullup]
|Voltage   I(typ)   I(min)   I(max)
-1.5V     79.77mA    55.2mA     133.5mA
-496mV    19.72mA    14.01mA    32.58mA
102mV     -2.891mA   -1.927mA   -5.109mA
2.034V    -17.98mA   -15.79mA   -27.08mA
2.172V    -31.95mA   -66.68mA   -42.37mA
2.31V     -60.53mA   -186.8mA   -67.92mA
2.356V    -89.72mA   -235.8mA   -77.05mA
2.448V    -194.7mA   -341.9mA   -93.98mA
2.54V     -332.1mA   -455mA     -152mA
2.632V    -483.4mA   -572.5mA   -318.5mA
2.77V     -722.8mA   -753.8mA   -641.9mA
3V        -1.137A    -1.064A    -1.229A
[Ramp]
| variable   typ   min   max
dV/dt_r   0.349/0.404n   0.222/0.493n   0.598/0.294n
dV/dt_f   0.341/0.379n   0.194/0.490n   0.541/0.314n
R_load = 50.000
[Rising Waveform]
R_fixture= 50.000
V_fixture= 0.0
V_fixture_min= 0.0
V_fixture_max= 0.0
|time   V(typ)   V(min)   V(max)
0s        4.678nV    51.7nV     2.482nV
803ps     23.15uV    31.46uV    -22.69mV
1.008ns   186uV      6.5uV      562.6mV
1.184ns   -751uV     6.5uV      798.4mV
1.598ns   -10.44mV   98.59uV    942.5mV
1.956ns   392mV      97.05uV    974.5mV
2.886ns   552.4mV    -15.96mV   993.8mV
3.596ns   570.7mV    295.9mV    996.4mV
4.584ns   578.4mV    355.8mV    997mV
20ns      581.2mV    370.1mV    997.2mV
[Rising Waveform]
R_fixture= 50.000
V_fixture= 1.500
V_fixture_min= 1.430
V_fixture_max= 1.580
|time   V(typ)   V(min)   V(max)
0s        932.1mV    1.107V     678.4mV
707ps     932.1mV    1.107V     668.1mV
772ps     932mV      1.107V     794mV
959ps     932.4mV    1.107V     1.452V
1.406ns   963.6mV    1.107V     1.566V
1.75ns    1.409V     1.107V     1.574V
2.097ns   1.485V     1.105V     1.577V
3.038ns   1.497V     1.373V     1.58V
3.662ns   1.499V     1.424V     1.58V
20ns      1.5V       1.43V      1.58V
[Falling Waveform]
R_fixture= 50.000
V_fixture= 1.500
V_fixture_min= 1.430
V_fixture_max= 1.580
|time   V(typ)   V(min)   V(max)
0s        1.5V       1.43V      1.58V
832ps     1.5V       1.43V      1.619V
1.016ns   1.5V       1.43V      1.137V
1.191ns   1.501V     1.43V      891.3mV
1.658ns   1.527V     1.43V      728.5mV
2.007ns   1.127V     1.43V      699.3mV
3.116ns   946.3mV    1.451V     680.1mV
3.777ns   937.3mV    1.174V     678.6mV
4.696ns   933.5mV    1.117V     678.6mV
20ns      932.1mV    1.107V     678.4mV
[Falling Waveform]
R_fixture= 50.000
V_fixture= 0.0
V_fixture_min= 0.0
V_fixture_max= 0.0
|time   V(typ)   V(min)   V(max)
0s        581.2mV    370.1mV    997.2mV
757ps     581.3mV    370.1mV    990.1mV
1.008ns   581.2mV    370.1mV    143.7mV
1.415ns   584mV      370.1mV    15.57mV
1.86ns    81.67mV    370.1mV    4.626mV
2.331ns   9.884mV    369.5mV    1.355mV
2.721ns   4.587mV    364.9mV    540.9uV
3.31ns    1.688mV    54.51mV    182.6uV
3.908ns   751uV      6.287mV    57.61uV
20ns      -348.3nV   110.7nV    -623.8nV
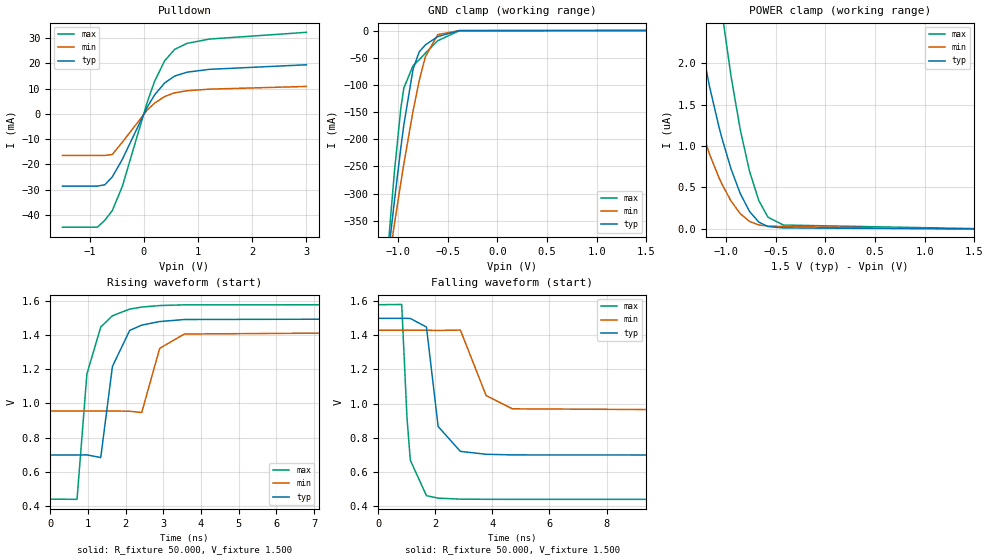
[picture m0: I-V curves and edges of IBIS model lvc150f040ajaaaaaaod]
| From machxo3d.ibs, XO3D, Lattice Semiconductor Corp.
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|   Model lvc150f040ajaaaaaaod
[Model] lvc150f040ajaaaaaaod
Model_type I/O_open_drain
Polarity   Non-Inverting
Enable   Active-Low
Vinl =  0.375V
Vinh =  1.125V
Vmeas =  0.750V
Cref =  0.0F
Rref = 10.00k
Vref = 1.50V
C_comp   4.200pF   3.800pF   7.500pF
[Temperature Range]   25.000   0.105k   -40.000
[Voltage Range]   1.500V   1.430V   1.580V
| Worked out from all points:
|   slope of the pulldown table from 0 to 0.225 V, typ, clamps not added: 27.2 ohm
|   GND clamp passes 1 mA (typ) near -0.44 V on its own axis
|   rising waveform, R_fixture 50.000, V_fixture 1.500: 20-80 % time 349ps typ, 377ps min, 350ps max; typ from 0.698 V to 1.5 V
|   falling waveform, R_fixture 50.000, V_fixture 1.500: 20-80 % time 362ps typ, 494ps min, 228ps max; typ from 1.5 V to 0.698 V
[Pulldown]
|Voltage   I(typ)   I(min)   I(max)
-1.5V     -28.65mA   -16.49mA   -44.94mA
-856mV    -28.65mA   -16.49mA   -44.94mA
-718mV    -28.13mA   -16.49mA   -42.19mA
-580mV    -24.97mA   -16.09mA   -38.34mA
-396mV    -18.07mA   -11.24mA   -28.78mA
64mV      2.693mA    1.538mA    4.627mA
202mV     7.594mA    4.31mA     13.05mA
386mV     12.28mA    6.899mA    21.09mA
570mV     15.01mA    8.357mA    25.6mA
800mV     16.55mA    9.183mA    27.99mA
1.214V    17.68mA    9.817mA    29.69mA
3V        19.48mA    10.89mA    32.36mA
[GND_clamp]
|Voltage   I(typ)   I(min)   I(max)
-1.5V     -1.124A    -960.6mA   -1.411A
-1.097V   -411.6mA   -430.5mA   -392.9mA
-1.066V   -360.7mA   -392.1mA   -323mA
-1.035V   -311mA     -354.2mA   -256.8mA
-973mV    -216.9mA   -280.8mA   -144.3mA
-942mV    -173.5mA   -245.5mA   -105.7mA
-849mV    -71.07mA   -147.7mA   -64.62mA
-787mV    -39.18mA   -92.07mA   -53.7mA
-725mV    -26.42mA   -48.02mA   -41.6mA
-601mV    -11.16mA   -7.547mA   -18.74mA
-384mV    -237.5uA   -103.4uA   -356uA
1.5V      0A         0A         0A
[POWER_clamp]
|Voltage   I(typ)   I(min)   I(max)
-1.5V     4.017uA    2.297uA    8.486uA
-1.321V   2.676uA    1.475uA    5.815uA
-1.166V   1.719uA    902.9nA    3.892uA
-1.073V   1.242uA    625.4nA    2.92uA
-1.042V   1.099uA    544.2nA    2.626uA
-949mV    723.1nA    335.9nA    1.84uA
-856mV    425.6nA    184nA      1.196uA
-763mV    211.1nA    90.94nA    695.5nA
-670mV    83.03nA    48.41nA    343nA
-577mV    29.38nA    34.61nA    141nA
-422mV    12.82nA    29.5nA     47.27nA
1.5V      0A         0A         4.136nA
[Ramp]
| variable   typ   min   max
dV/dt_r   0.482/0.348n   0.285/0.372n   0.685/0.350n
dV/dt_f   0.481/0.361n   0.285/0.488n   0.685/0.229n
R_load = 50.000
[Rising Waveform]
R_fixture= 50.000
V_fixture= 1.500
V_fixture_min= 1.430
V_fixture_max= 1.580
|time   V(typ)   V(min)   V(max)
0s        697.5mV    955.7mV    438.5mV
710ps     697.5mV    955.7mV    437.5mV
972ps     698mV      955.7mV    1.173V
1.339ns   682.5mV    955.6mV    1.448V
1.649ns   1.217V     955.8mV    1.514V
2.107ns   1.428V     954mV      1.553V
2.426ns   1.459V     946.6mV    1.565V
2.903ns   1.48V      1.323V     1.574V
3.559ns   1.492V     1.407V     1.578V
20ns      1.5V       1.43V      1.58V
[Falling Waveform]
R_fixture= 50.000
V_fixture= 1.500
V_fixture_min= 1.430
V_fixture_max= 1.580
|time   V(typ)   V(min)   V(max)
0s        1.5V       1.43V      1.58V
824ps     1.5V       1.43V      1.581V
1.008ns   1.5V       1.43V      919.6mV
1.126ns   1.499V     1.43V      667.5mV
1.691ns   1.449V     1.43V      459.9mV
2.101ns   865.3mV    1.429V     445.6mV
2.88ns    719.6mV    1.431V     439.6mV
3.782ns   702.8mV    1.047V     438.7mV
4.7ns     698.9mV    969.2mV    438.5mV
20ns      697.5mV    955.7mV    438.5mV
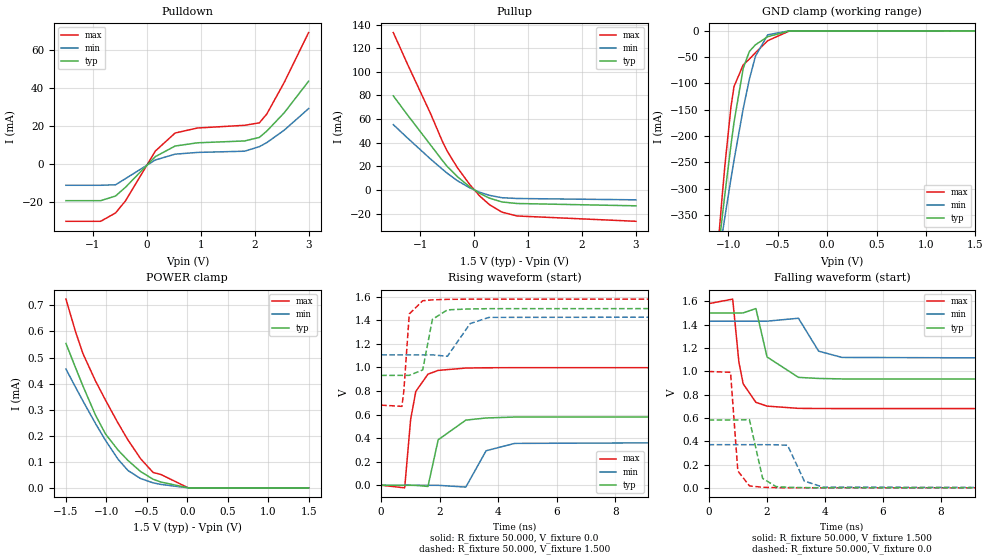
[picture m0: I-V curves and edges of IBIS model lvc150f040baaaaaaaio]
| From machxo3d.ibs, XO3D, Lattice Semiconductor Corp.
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|   Model lvc150f040baaaaaaaio
[Model] lvc150f040baaaaaaaio
Model_type I/O
Polarity   Non-Inverting
Enable   Active-Low
Vinl =  0.375V
Vinh =  1.125V
Vmeas =  0.750V
Cref =  0.0F
Rref =  1.000M
Vref =  0.0V
C_comp   4.200pF   3.800pF   7.500pF
[Temperature Range]   25.000   0.105k   -40.000
[Voltage Range]   1.500V   1.430V   1.580V
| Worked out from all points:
|   slope of the pulldown table from 0 to 0.225 V, typ, clamps not added: 40.7 ohm
|   slope of the pullup table from 0 to 0.225 V, typ, clamps not added: 38.9 ohm
|   GND clamp passes 1 mA (typ) near -0.44 V on its own axis
|   rising waveform, R_fixture 50.000, V_fixture 0.0: 20-80 % time 415ps typ, 499ps min, 292ps max; typ from 0 V to 0.582 V
|   rising waveform, R_fixture 50.000, V_fixture 1.500: 20-80 % time 260ps typ, 435ps min, 140ps max; typ from 0.933 V to 1.5 V
|   falling waveform, R_fixture 50.000, V_fixture 1.500: 20-80 % time 378ps typ, 482ps min, 315ps max; typ from 1.5 V to 0.933 V
|   falling waveform, R_fixture 50.000, V_fixture 0.0: 20-80 % time 246ps typ, 400ps min, 149ps max; typ from 0.582 V to 0 V
[Pulldown]
|Voltage   I(typ)   I(min)   I(max)
-1.5V     -19.1mA    -10.99mA   -29.96mA
-856mV    -19.1mA    -10.99mA   -29.96mA
-580mV    -16.64mA   -10.73mA   -25.56mA
-396mV    -12.04mA   -7.496mA   -19.19mA
156mV     4.064mA    2.312mA    6.984mA
524mV     9.661mA    5.388mA    16.51mA
938mV     11.37mA    6.303mA    19.16mA
1.812V    12.34mA    6.942mA    20.58mA
2.088V    14.22mA    9.341mA    21.9mA
2.226V    17.58mA    11.5mA     26.59mA
2.548V    27.18mA    18.02mA    43.16mA
3V        43.78mA    29.38mA    69.41mA
[Pullup]
|Voltage   I(typ)   I(min)   I(max)
-1.5V     79.63mA    55.26mA    133.2mA
-1.232V   63.2mA     43.78mA    106mA
-818mV    38.59mA    26.52mA    65.5mA
-588mV    24.87mA    17.47mA    40.94mA
-496mV    19.7mA     14.01mA    32.54mA
-312mV    11.25mA    7.838mA    18.9mA
-82mV     2.627mA    1.78mA     4.548mA
102mV     -2.891mA   -1.927mA   -5.109mA
286mV     -6.99mA    -4.605mA   -12.56mA
516mV     -10.15mA   -6.555mA   -18.77mA
792mV     -11.45mA   -7.225mA   -22.01mA
3V        -13.42mA   -8.343mA   -26.52mA
[GND_clamp]
|Voltage   I(typ)   I(min)   I(max)
-1.5V     -1.124A    -960.6mA   -1.411A
-1.097V   -411.6mA   -430.5mA   -392.9mA
-1.066V   -360.7mA   -392.1mA   -323mA
-1.035V   -311mA     -354.2mA   -256.7mA
-973mV    -216.8mA   -280.8mA   -144.3mA
-942mV    -173.5mA   -245.5mA   -105.7mA
-849mV    -71.06mA   -147.7mA   -64.61mA
-787mV    -39.17mA   -92.07mA   -53.7mA
-725mV    -26.41mA   -48.02mA   -41.6mA
-601mV    -11.16mA   -7.552mA   -18.74mA
-384mV    -258.6uA   -114.9uA   -396.2uA
1.5V      -41.68nA   0A         -8.283uA
[POWER_clamp]
|Voltage   I(typ)   I(min)   I(max)
-1.5V     553.8uA    455.7uA    723.9uA
-1.383V   462uA      386.8uA    600.3uA
-1.29V    390.6uA    333.2uA    514.8uA
-1.135V   279.1uA    247uA      410.2uA
-1.011V   206.7uA    182uA      336.5uA
-856mV    145uA      109.7uA    248.3uA
-732mV    104.8uA    66.29uA    183.2uA
-577mV    62.52uA    35.6uA     111.7uA
-422mV    33.03uA    19.13uA    58.98uA
-329mV    22.6uA     13.31uA    51.73uA
12mV      0A         0A         0A
1.5V      0A         0A         0A
[Ramp]
| variable   typ   min   max
dV/dt_r   0.349/0.408n   0.222/0.495n   0.599/0.298n
dV/dt_f   0.340/0.381n   0.194/0.491n   0.540/0.316n
R_load = 50.000
[Rising Waveform]
R_fixture= 50.000
V_fixture= 0.0
V_fixture_min= 0.0
V_fixture_max= 0.0
|time   V(typ)   V(min)   V(max)
0s        486.4uV    318.7uV    761.2uV
803ps     536uV      326.8uV    -21.54mV
1.006ns   664uV      326.8uV    559.1mV
1.182ns   -256.6uV   326.8uV    796.7mV
1.598ns   -9.576mV   415uV      943mV
1.947ns   386.4mV    46.79uV    975.2mV
2.891ns   553.3mV    -14.97mV   995.2mV
3.584ns   571.6mV    293.5mV    997.6mV
4.558ns   579.3mV    355.7mV    998.2mV
20ns      582.4mV    370.7mV    998.4mV
[Rising Waveform]
R_fixture= 50.000
V_fixture= 1.500
V_fixture_min= 1.430
V_fixture_max= 1.580
|time   V(typ)   V(min)   V(max)
0s        933mV      1.107V     680.4mV
707ps     933.1mV    1.107V     670.1mV
772ps     933mV      1.107V     796.1mV
960ps     933.3mV    1.107V     1.454V
1.418ns   979.1mV    1.107V     1.566V
1.749ns   1.408V     1.107V     1.574V
2.262ns   1.489V     1.095V     1.578V
3.041ns   1.497V     1.373V     1.58V
3.687ns   1.499V     1.425V     1.58V
20ns      1.5V       1.43V      1.58V
[Falling Waveform]
R_fixture= 50.000
V_fixture= 1.500
V_fixture_min= 1.430
V_fixture_max= 1.580
|time   V(typ)   V(min)   V(max)
0s        1.5V       1.43V      1.58V
832ps     1.5V       1.43V      1.619V
1.045ns   1.5V       1.43V      1.079V
1.193ns   1.501V     1.43V      892.3mV
1.63ns    1.538V     1.43V      733.9mV
2.014ns   1.123V     1.43V      701.3mV
3.096ns   947.9mV    1.455V     682.2mV
3.789ns   938.7mV    1.173V     680.8mV
4.594ns   934.7mV    1.119V     680.5mV
20ns      933mV      1.107V     680.4mV
[Falling Waveform]
R_fixture= 50.000
V_fixture= 0.0
V_fixture_min= 0.0
V_fixture_max= 0.0
|time   V(typ)   V(min)   V(max)
0s        582.4mV    370.7mV    998.4mV
757ps     582.4mV    370.7mV    991.4mV
1.008ns   582.4mV    370.7mV    146.1mV
1.409ns   585.4mV    370.7mV    16.93mV
1.864ns   80.85mV    370.7mV    5.449mV
2.329ns   10.78mV    370mV      2.118mV
2.722ns   5.349mV    365.3mV    1.305mV
3.297ns   2.384mV    58.79mV    945.9uV
3.942ns   1.186mV    6.42mV     819.7uV
20ns      486.3uV    318.6uV    761.1uV
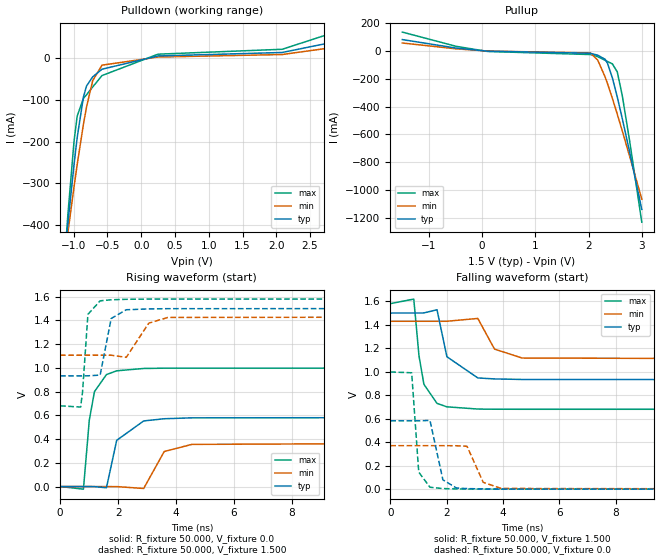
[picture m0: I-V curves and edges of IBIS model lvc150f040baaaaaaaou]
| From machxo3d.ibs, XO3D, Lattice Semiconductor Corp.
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|   Model lvc150f040baaaaaaaou
[Model] lvc150f040baaaaaaaou
Model_type Output
Polarity   Non-Inverting
Enable   Active-High
Vmeas =  0.750V
Cref =  0.0F
Rref =  1.000M
Vref =  0.0V
C_comp   4.200pF   3.800pF   7.500pF
[Temperature Range]   25.000   0.105k   -40.000
[Voltage Range]   1.500V   1.430V   1.580V
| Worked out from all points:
|   slope of the pulldown table from 0 to 0.225 V, typ, clamps not added: 40.7 ohm
|   slope of the pullup table from 0 to 0.225 V, typ, clamps not added: 38.8 ohm
|   rising waveform, R_fixture 50.000, V_fixture 0.0: 20-80 % time 418ps typ, 488ps min, 296ps max; typ from 0 V to 0.582 V
|   rising waveform, R_fixture 50.000, V_fixture 1.500: 20-80 % time 258ps typ, 437ps min, 139ps max; typ from 0.933 V to 1.5 V
|   falling waveform, R_fixture 50.000, V_fixture 1.500: 20-80 % time 378ps typ, 484ps min, 314ps max; typ from 1.5 V to 0.933 V
|   falling waveform, R_fixture 50.000, V_fixture 0.0: 20-80 % time 245ps typ, 399ps min, 149ps max; typ from 0.582 V to 0 V
[Pulldown]
|Voltage   I(typ)   I(min)   I(max)
-1.5V     -1.125A    -961.3mA   -1.413A
-1.132V   -473mA     -476mA     -480.5mA
-1.086V   -396.8mA   -418.5mA   -375.7mA
-994mV    -253.7mA   -307.5mA   -198.1mA
-948mV    -190mA     -254.9mA   -138.6mA
-856mV    -93.03mA   -158.7mA   -95.91mA
-810mV    -66.24mA   -117mA     -87.26mA
-718mV    -44.13mA   -53.14mA   -68.36mA
-580mV    -25.79mA   -16.16mA   -41.04mA
248mV     5.949mA    3.37mA     10.22mA
2.088V    14.29mA    9.39mA     21.99mA
3V        44.33mA    29.88mA    70.05mA
[Pullup]
|Voltage   I(typ)   I(min)   I(max)
-1.5V     80.18mA    55.72mA    133.9mA
-496mV    19.75mA    14.03mA    32.62mA
102mV     -2.897mA   -1.93mA    -5.12mA
2.034V    -18mA      -15.8mA    -27.11mA
2.172V    -31.96mA   -66.69mA   -42.39mA
2.31V     -60.54mA   -186.8mA   -67.94mA
2.356V    -89.72mA   -235.8mA   -77.06mA
2.448V    -194.7mA   -341.9mA   -93.99mA
2.54V     -332.1mA   -455mA     -152mA
2.632V    -483.4mA   -572.5mA   -318.5mA
2.77V     -722.8mA   -753.8mA   -641.9mA
3V        -1.137A    -1.064A    -1.229A
[Ramp]
| variable   typ   min   max
dV/dt_r   0.349/0.404n   0.222/0.493n   0.599/0.296n
dV/dt_f   0.340/0.380n   0.194/0.491n   0.540/0.315n
R_load = 50.000
[Rising Waveform]
R_fixture= 50.000
V_fixture= 0.0
V_fixture_min= 0.0
V_fixture_max= 0.0
|time   V(typ)   V(min)   V(max)
0s        486.4uV    318.7uV    761.2uV
803ps     535uV      350.7uV    -21.59mV
1.006ns   668.9uV    325.7uV    560.2mV
1.184ns   -256.9uV   325.7uV    800.3mV
1.598ns   -9.631mV   415.1uV    943.8mV
1.951ns   389.8mV    54.62uV    975.7mV
2.882ns   553.2mV    -15.79mV   995.2mV
3.592ns   571.7mV    295.7mV    997.7mV
4.545ns   579.4mV    355.7mV    998.2mV
20ns      582.4mV    370.7mV    998.4mV
[Rising Waveform]
R_fixture= 50.000
V_fixture= 1.500
V_fixture_min= 1.430
V_fixture_max= 1.580
|time   V(typ)   V(min)   V(max)
0s        933mV      1.107V     680.4mV
707ps     933mV      1.107V     670.1mV
772ps     933mV      1.107V     796.1mV
958ps     933.4mV    1.107V     1.451V
1.38ns    939.4mV    1.107V     1.565V
1.761ns   1.416V     1.107V     1.574V
2.281ns   1.49V      1.089V     1.578V
3.059ns   1.497V     1.377V     1.58V
3.714ns   1.499V     1.425V     1.58V
20ns      1.5V       1.43V      1.58V
[Falling Waveform]
R_fixture= 50.000
V_fixture= 1.500
V_fixture_min= 1.430
V_fixture_max= 1.580
|time   V(typ)   V(min)   V(max)
0s        1.5V       1.43V      1.58V
832ps     1.5V       1.43V      1.619V
1.016ns   1.5V       1.43V      1.137V
1.191ns   1.501V     1.43V      893.2mV
1.656ns   1.528V     1.43V      730.8mV
2.007ns   1.128V     1.43V      701.4mV
3.104ns   947.4mV    1.454V     682.5mV
3.697ns   938.9mV    1.193V     680.9mV
4.674ns   934.5mV    1.117V     680.6mV
20ns      933mV      1.107V     680.4mV
[Falling Waveform]
R_fixture= 50.000
V_fixture= 0.0
V_fixture_min= 0.0
V_fixture_max= 0.0
|time   V(typ)   V(min)   V(max)
0s        582.4mV    370.7mV    998.4mV
757ps     582.4mV    370.7mV    991.4mV
1.008ns   582.4mV    370.7mV    145.2mV
1.407ns   585.5mV    370.7mV    16.75mV
1.865ns   79.63mV    370.6mV    5.501mV
2.346ns   10.01mV    370mV      2.177mV
2.721ns   5.241mV    365.5mV    1.344mV
3.296ns   2.279mV    58.63mV    966.9uV
3.937ns   1.125mV    6.226mV    830.2uV
20ns      486.1uV    318.6uV    760.8uV
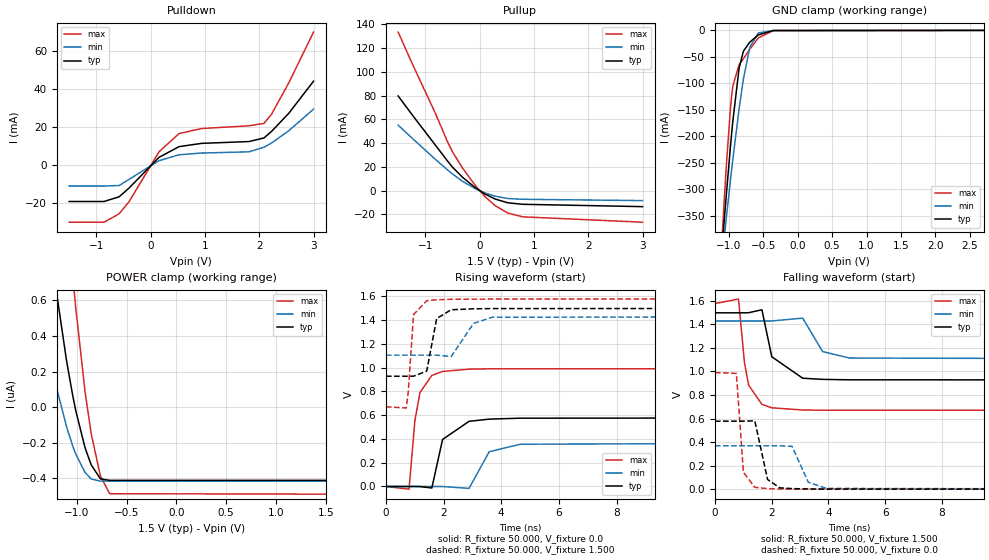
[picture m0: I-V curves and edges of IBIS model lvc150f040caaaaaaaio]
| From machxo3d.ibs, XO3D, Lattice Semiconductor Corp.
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|   Model lvc150f040caaaaaaaio
[Model] lvc150f040caaaaaaaio
Model_type I/O
Polarity   Non-Inverting
Enable   Active-Low
Vinl =  0.375V
Vinh =  1.125V
Vmeas =  0.750V
Cref =  0.0F
Rref =  1.000M
Vref =  0.0V
C_comp   4.200pF   3.800pF   7.500pF
[Temperature Range]   25.000   0.105k   -40.000
[Voltage Range]   1.500V   1.430V   1.580V
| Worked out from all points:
|   slope of the pulldown table from 0 to 0.225 V, typ, clamps not added: 40.7 ohm
|   slope of the pullup table from 0 to 0.225 V, typ, clamps not added: 38.9 ohm
|   GND clamp passes 1 mA (typ) near -0.43 V on its own axis
|   rising waveform, R_fixture 50.000, V_fixture 0.0: 20-80 % time 404ps typ, 492ps min, 293ps max; typ from 0 V to 0.577 V
|   rising waveform, R_fixture 50.000, V_fixture 1.500: 20-80 % time 261ps typ, 436ps min, 140ps max; typ from 0.928 V to 1.5 V
|   falling waveform, R_fixture 50.000, V_fixture 1.500: 20-80 % time 371ps typ, 478ps min, 313ps max; typ from 1.5 V to 0.928 V
|   falling waveform, R_fixture 50.000, V_fixture 0.0: 20-80 % time 248ps typ, 398ps min, 147ps max; typ from 0.577 V to 0 V
[Pulldown]
|Voltage   I(typ)   I(min)   I(max)
-1.5V     -19.1mA    -10.99mA   -29.96mA
-856mV    -19.1mA    -10.99mA   -29.96mA
-580mV    -16.64mA   -10.73mA   -25.56mA
-396mV    -12.04mA   -7.496mA   -19.19mA
156mV     4.064mA    2.312mA    6.984mA
524mV     9.661mA    5.388mA    16.51mA
938mV     11.37mA    6.303mA    19.16mA
1.812V    12.33mA    6.941mA    20.58mA
2.088V    14.23mA    9.35mA     21.86mA
2.226V    17.61mA    11.53mA    26.61mA
2.548V    27.26mA    18.08mA    43.3mA
3V        43.99mA    29.32mA    69.73mA
[Pullup]
|Voltage   I(typ)   I(min)   I(max)
-1.5V     79.83mA    55.23mA    133.6mA
-1.232V   63.35mA    43.82mA    106.2mA
-818mV    38.63mA    26.55mA    65.6mA
-588mV    24.88mA    17.48mA    40.94mA
-496mV    19.69mA    14.01mA    32.5mA
-312mV    11.24mA    7.837mA    18.9mA
-82mV     2.627mA    1.78mA     4.548mA
102mV     -2.891mA   -1.927mA   -5.109mA
286mV     -6.99mA    -4.605mA   -12.56mA
516mV     -10.15mA   -6.555mA   -18.77mA
792mV     -11.45mA   -7.225mA   -22.01mA
3V        -13.42mA   -8.343mA   -26.52mA
[GND_clamp]
|Voltage   I(typ)   I(min)   I(max)
-1.5V     -1.124A    -960.6mA   -1.411A
-1.097V   -411.6mA   -430.5mA   -393mA
-1.066V   -360.7mA   -392.1mA   -323mA
-1.035V   -311mA     -354.2mA   -256.8mA
-973mV    -216.9mA   -280.8mA   -144.3mA
-942mV    -173.5mA   -245.5mA   -105.7mA
-849mV    -71.09mA   -147.7mA   -64.66mA
-787mV    -39.21mA   -92.09mA   -53.75mA
-694mV    -22.05mA   -31.84mA   -35.55mA
-570mV    -8.285mA   -4.678mA   -14.06mA
-353mV    -178.3uA   -91.12uA   -279.1uA
3V        108.1uA    41.24uA    254.4uA
[POWER_clamp]
|Voltage   I(typ)   I(min)   I(max)
-1.5V     2.264uA    1.09uA     5.325uA
-1.383V   1.543uA    646.9nA    3.832uA
-1.29V    1.045uA    348.8nA    2.802uA
-1.197V   619.1nA    96nA       1.914uA
-1.104V   264.3nA    -108.5nA   1.168uA
-1.042V   67.87nA    -217.5nA   747.1nA
-1.011V   -18.19nA   -263.5nA   559.8nA
-918mV    -227nA     -366.2nA   89.62nA
-856mV    -324nA     -403.7nA   -147.4nA
-763mV    -403.1nA   -415.9nA   -387.4nA
-670mV    -411.5nA   -415.9nA   -486.7nA
1.5V      -411.5nA   -415.9nA   -489.1nA
[Ramp]
| variable   typ   min   max
dV/dt_r   0.346/0.404n   0.221/0.491n   0.594/0.299n
dV/dt_f   0.342/0.379n   0.194/0.491n   0.544/0.313n
R_load = 50.000
[Rising Waveform]
R_fixture= 50.000
V_fixture= 0.0
V_fixture_min= 0.0
V_fixture_max= 0.0
|time   V(typ)   V(min)   V(max)
0s        4.549nV    50.98nV    2.322nV
803ps     24.5uV     10.5uV     -22.57mV
1.006ns   180.9uV    10.5uV     555.7mV
1.183ns   -750.6uV   10.5uV     790.7mV
1.594ns   -12.6mV    101.6uV    934.7mV
1.965ns   395.4mV    -311.1uV   968mV
2.884ns   548.3mV    -15.96mV   987.3mV
3.584ns   566.7mV    292.4mV    989.9mV
4.663ns   574.7mV    355.6mV    990.5mV
20ns      577.2mV    368.8mV    990.6mV
[Rising Waveform]
R_fixture= 50.000
V_fixture= 1.500
V_fixture_min= 1.430
V_fixture_max= 1.580
|time   V(typ)   V(min)   V(max)
0s        927.7mV    1.105V     670.5mV
707ps     927.7mV    1.105V     660.3mV
774ps     927.6mV    1.105V     791.7mV
959ps     928mV      1.105V     1.446V
1.416ns   971.1mV    1.105V     1.563V
1.761ns   1.413V     1.105V     1.571V
2.262ns   1.487V     1.093V     1.575V
3.041ns   1.495V     1.372V     1.576V
3.686ns   1.497V     1.424V     1.577V
20ns      1.498V     1.429V     1.577V
[Falling Waveform]
R_fixture= 50.000
V_fixture= 1.500
V_fixture_min= 1.430
V_fixture_max= 1.580
|time   V(typ)   V(min)   V(max)
0s        1.498V     1.429V     1.577V
832ps     1.498V     1.429V     1.615V
1.044ns   1.498V     1.429V     1.071V
1.191ns   1.499V     1.429V     883.1mV
1.658ns   1.524V     1.429V     720.4mV
2.005ns   1.125V     1.429V     691.3mV
3.096ns   942.5mV    1.453V     672.6mV
3.796ns   932.8mV    1.169V     671mV
4.739ns   929mV      1.114V     670.6mV
20ns      927.7mV    1.105V     670.5mV
[Falling Waveform]
R_fixture= 50.000
V_fixture= 0.0
V_fixture_min= 0.0
V_fixture_max= 0.0
|time   V(typ)   V(min)   V(max)
0s        577.2mV    368.8mV    990.6mV
757ps     577.3mV    368.8mV    983.3mV
1.006ns   577.3mV    368.8mV    142.7mV
1.406ns   580.4mV    368.8mV    15.63mV
1.857ns   82.11mV    368.8mV    4.757mV
2.287ns   11.12mV    368.4mV    1.438mV
2.721ns   4.729mV    363.6mV    590.4uV
3.294ns   1.781mV    58.4mV     129.7uV
3.938ns   631.9uV    6.034mV    71.45uV
20ns      -288.2nV   -40nV      -37.41nV
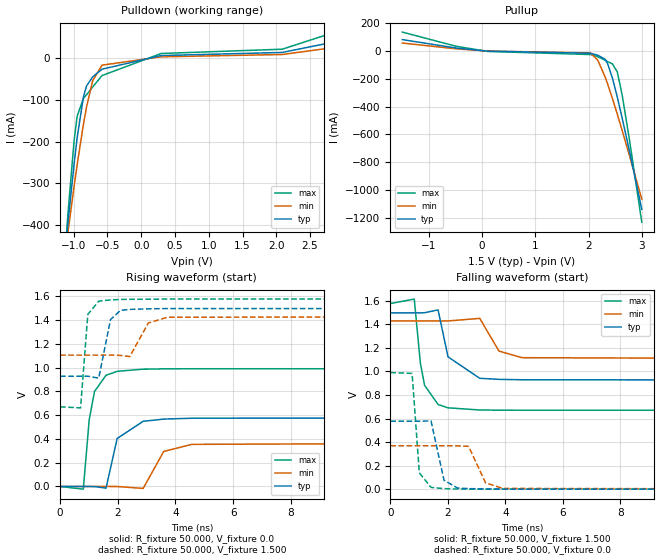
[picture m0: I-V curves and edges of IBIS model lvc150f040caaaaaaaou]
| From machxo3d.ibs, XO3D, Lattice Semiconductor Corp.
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|   Model lvc150f040caaaaaaaou
[Model] lvc150f040caaaaaaaou
Model_type Output
Polarity   Non-Inverting
Enable   Active-High
Vmeas =  0.750V
Cref =  0.0F
Rref =  1.000M
Vref =  0.0V
C_comp   4.200pF   3.800pF   7.500pF
[Temperature Range]   25.000   0.105k   -40.000
[Voltage Range]   1.500V   1.430V   1.580V
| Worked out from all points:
|   slope of the pulldown table from 0 to 0.225 V, typ, clamps not added: 40.4 ohm
|   slope of the pullup table from 0 to 0.225 V, typ, clamps not added: 38.9 ohm
|   rising waveform, R_fixture 50.000, V_fixture 0.0: 20-80 % time 411ps typ, 486ps min, 290ps max; typ from 0 V to 0.577 V
|   rising waveform, R_fixture 50.000, V_fixture 1.500: 20-80 % time 260ps typ, 436ps min, 140ps max; typ from 0.928 V to 1.5 V
|   falling waveform, R_fixture 50.000, V_fixture 1.500: 20-80 % time 371ps typ, 481ps min, 312ps max; typ from 1.5 V to 0.928 V
|   falling waveform, R_fixture 50.000, V_fixture 0.0: 20-80 % time 246ps typ, 399ps min, 147ps max; typ from 0.577 V to 0 V
[Pulldown]
|Voltage   I(typ)   I(min)   I(max)
-1.5V     -1.125A    -961.3mA   -1.413A
-1.132V   -473mA     -476mA     -480.5mA
-1.086V   -396.8mA   -418.5mA   -375.7mA
-994mV    -253.7mA   -307.5mA   -198.1mA
-948mV    -190.1mA   -254.9mA   -138.7mA
-856mV    -93.06mA   -158.7mA   -95.96mA
-810mV    -66.28mA   -117mA     -87.3mA
-718mV    -44.17mA   -53.17mA   -68.41mA
-580mV    -25.84mA   -16.2mA    -41.11mA
294mV     6.851mA    3.862mA    11.81mA
2.088V    14.33mA    9.389mA    22.11mA
3V        44.1mA     29.36mA    69.99mA
[Pullup]
|Voltage   I(typ)   I(min)   I(max)
-1.5V     79.94mA    55.27mA    133.8mA
-496mV    19.8mA     14.05mA    32.75mA
102mV     -2.791mA   -1.89mA    -4.87mA
2.034V    -18.04mA   -15.83mA   -27.19mA
2.172V    -31.99mA   -66.7mA    -42.44mA
2.31V     -60.56mA   -186.8mA   -67.97mA
2.356V    -89.75mA   -235.8mA   -77.09mA
2.448V    -194.7mA   -341.9mA   -94.02mA
2.54V     -332.1mA   -455mA     -152mA
2.632V    -483.5mA   -572.5mA   -318.5mA
2.77V     -722.8mA   -753.8mA   -642mA
3V        -1.137A    -1.064A    -1.229A
[Ramp]
| variable   typ   min   max
dV/dt_r   0.346/0.401n   0.221/0.492n   0.594/0.297n
dV/dt_f   0.342/0.378n   0.194/0.485n   0.544/0.312n
R_load = 50.000
[Rising Waveform]
R_fixture= 50.000
V_fixture= 0.0
V_fixture_min= 0.0
V_fixture_max= 0.0
|time   V(typ)   V(min)   V(max)
0s        4.508nV    51.14nV    2.279nV
803ps     23.16uV    31.41uV    -22.61mV
1.008ns   186.2uV    6.441uV    560.9mV
1.191ns   -751.2uV   6.441uV    798.8mV
1.592ns   -13.71mV   98.43uV    936mV
1.978ns   403.7mV    -281.8uV   968.9mV
2.881ns   548.6mV    -16.31mV   987mV
3.593ns   566.9mV    294.7mV    989.9mV
4.57ns    574.4mV    354.4mV    990.5mV
20ns      577.2mV    368.8mV    990.6mV
[Rising Waveform]
R_fixture= 50.000
V_fixture= 1.500
V_fixture_min= 1.430
V_fixture_max= 1.580
|time   V(typ)   V(min)   V(max)
0s        927.7mV    1.105V     670.5mV
708ps     927.7mV    1.105V     661mV
960ps     928mV      1.105V     1.448V
1.338ns   911.2mV    1.105V     1.559V
1.747ns   1.404V     1.106V     1.57V
2.094ns   1.482V     1.103V     1.574V
2.415ns   1.49V      1.093V     1.575V
3.061ns   1.495V     1.376V     1.576V
3.724ns   1.497V     1.424V     1.577V
20ns      1.498V     1.429V     1.577V
[Falling Waveform]
R_fixture= 50.000
V_fixture= 1.500
V_fixture_min= 1.430
V_fixture_max= 1.580
|time   V(typ)   V(min)   V(max)
0s        1.498V     1.429V     1.577V
832ps     1.498V     1.429V     1.615V
1.044ns   1.498V     1.429V     1.071V
1.191ns   1.499V     1.429V     882.2mV
1.66ns    1.523V     1.429V     719.4mV
2.005ns   1.124V     1.429V     691mV
3.108ns   941.8mV    1.451V     672.5mV
3.777ns   932.9mV    1.173V     671.1mV
4.579ns   929.3mV    1.117V     670.6mV
20ns      927.7mV    1.105V     670.5mV
[Falling Waveform]
R_fixture= 50.000
V_fixture= 0.0
V_fixture_min= 0.0
V_fixture_max= 0.0
|time   V(typ)   V(min)   V(max)
0s        577.2mV    368.8mV    990.6mV
757ps     577.3mV    368.8mV    983.3mV
1.008ns   577.2mV    368.8mV    138.9mV
1.414ns   580.2mV    368.8mV    15.1mV
1.866ns   76.45mV    368.7mV    4.551mV
2.331ns   9.704mV    368.1mV    1.32mV
2.721ns   4.49mV     363.6mV    521.8uV
3.309ns   1.911mV    54.1mV     172.1uV
3.912ns   708.1uV    6.139mV    53.41uV
20ns      -184.8nV   -219.5nV   25.61nV
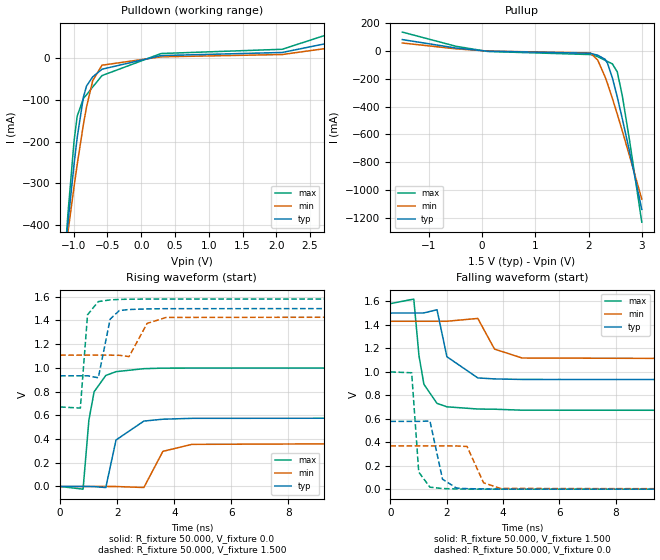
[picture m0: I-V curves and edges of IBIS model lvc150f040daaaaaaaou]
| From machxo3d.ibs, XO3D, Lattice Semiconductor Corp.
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|   Model lvc150f040daaaaaaaou
[Model] lvc150f040daaaaaaaou
Model_type Output
Polarity   Non-Inverting
Enable   Active-High
Vmeas =  0.750V
Cref =  0.0F
Rref =  1.000M
Vref =  0.0V
C_comp   4.200pF   3.800pF   7.500pF
[Temperature Range]   25.000   0.105k   -40.000
[Voltage Range]   1.500V   1.430V   1.580V
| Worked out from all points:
|   slope of the pulldown table from 0 to 0.225 V, typ, clamps not added: 40.4 ohm
|   slope of the pullup table from 0 to 0.225 V, typ, clamps not added: 38.8 ohm
|   rising waveform, R_fixture 50.000, V_fixture 0.0: 20-80 % time 410ps typ, 487ps min, 297ps max; typ from 0 V to 0.577 V
|   rising waveform, R_fixture 50.000, V_fixture 1.500: 20-80 % time 260ps typ, 436ps min, 141ps max; typ from 0.933 V to 1.5 V
|   falling waveform, R_fixture 50.000, V_fixture 1.500: 20-80 % time 378ps typ, 484ps min, 324ps max; typ from 1.5 V to 0.933 V
|   falling waveform, R_fixture 50.000, V_fixture 0.0: 20-80 % time 246ps typ, 399ps min, 149ps max; typ from 0.577 V to 0 V
[Pulldown]
|Voltage   I(typ)   I(min)   I(max)
-1.5V     -1.125A    -961.3mA   -1.413A
-1.132V   -473mA     -476mA     -480.5mA
-1.086V   -396.8mA   -418.5mA   -375.7mA
-994mV    -253.7mA   -307.5mA   -198.1mA
-948mV    -190.1mA   -254.9mA   -138.7mA
-856mV    -93.06mA   -158.7mA   -95.96mA
-810mV    -66.28mA   -117mA     -87.3mA
-718mV    -44.17mA   -53.17mA   -68.41mA
-580mV    -25.84mA   -16.2mA    -41.11mA
294mV     6.851mA    3.862mA    11.81mA
2.088V    14.29mA    9.39mA     21.99mA
3V        44.33mA    29.88mA    70.05mA
[Pullup]
|Voltage   I(typ)   I(min)   I(max)
-1.5V     80.18mA    55.72mA    133.9mA
-496mV    19.75mA    14.03mA    32.62mA
102mV     -2.897mA   -1.93mA    -5.12mA
2.034V    -18.04mA   -15.83mA   -27.19mA
2.172V    -31.99mA   -66.7mA    -42.44mA
2.31V     -60.56mA   -186.8mA   -67.97mA
2.356V    -89.75mA   -235.8mA   -77.09mA
2.448V    -194.7mA   -341.9mA   -94.02mA
2.54V     -332.1mA   -455mA     -152mA
2.632V    -483.5mA   -572.5mA   -318.5mA
2.77V     -722.8mA   -753.8mA   -642mA
3V        -1.137A    -1.064A    -1.229A
[Ramp]
| variable   typ   min   max
dV/dt_r   0.346/0.401n   0.221/0.492n   0.599/0.304n
dV/dt_f   0.340/0.380n   0.194/0.491n   0.546/0.326n
R_load = 50.000
[Rising Waveform]
R_fixture= 50.000
V_fixture= 0.0
V_fixture_min= 0.0
V_fixture_max= 0.0
|time   V(typ)   V(min)   V(max)
0s        4.508nV    51.14nV    2.279nV
803ps     23.13uV    31.38uV    -22.61mV
1.008ns   186.2uV    6.384uV    560.9mV
1.191ns   -751.2uV   6.384uV    798.8mV
1.6ns     -9.132mV   98.44uV    936mV
1.958ns   392mV      -281.8uV   967.9mV
2.934ns   551.3mV    -8.567mV   993.1mV
3.601ns   567.1mV    296.2mV    997.8mV
4.616ns   574.5mV    355.1mV    998.3mV
20ns      577.2mV    368.8mV    998.4mV
[Rising Waveform]
R_fixture= 50.000
V_fixture= 1.500
V_fixture_min= 1.430
V_fixture_max= 1.580
|time   V(typ)   V(min)   V(max)
0s        933mV      1.107V     670.5mV
708ps     933mV      1.107V     661mV
960ps     933.4mV    1.107V     1.448V
1.338ns   916.5mV    1.107V     1.559V
1.752ns   1.411V     1.107V     1.573V
2.075ns   1.483V     1.106V     1.577V
2.415ns   1.492V     1.095V     1.579V
3.049ns   1.497V     1.375V     1.58V
3.714ns   1.499V     1.425V     1.58V
20ns      1.5V       1.43V      1.58V
[Falling Waveform]
R_fixture= 50.000
V_fixture= 1.500
V_fixture_min= 1.430
V_fixture_max= 1.580
|time   V(typ)   V(min)   V(max)
0s        1.5V       1.43V      1.58V
832ps     1.5V       1.43V      1.619V
1.016ns   1.5V       1.43V      1.137V
1.191ns   1.501V     1.43V      893.2mV
1.656ns   1.528V     1.43V      730.8mV
2.007ns   1.128V     1.43V      701.4mV
3.104ns   947.4mV    1.454V     682.5mV
3.697ns   938.9mV    1.193V     680.9mV
4.674ns   934.5mV    1.117V     672.6mV
20ns      933mV      1.107V     670.5mV
[Falling Waveform]
R_fixture= 50.000
V_fixture= 0.0
V_fixture_min= 0.0
V_fixture_max= 0.0
|time   V(typ)   V(min)   V(max)
0s        577.2mV    368.8mV    998.4mV
757ps     577.3mV    368.8mV    991.4mV
1.008ns   577.2mV    368.8mV    145.2mV
1.407ns   580.4mV    368.8mV    16.75mV
1.851ns   85.01mV    368.7mV    5.488mV
2.349ns   9.193mV    368.1mV    1.613mV
2.721ns   4.49mV     363.6mV    690.5uV
3.309ns   1.911mV    54.1mV     174.3uV
3.912ns   708.1uV    6.139mV    53.38uV
20ns      -184.8nV   -202.8nV   -394.5nV
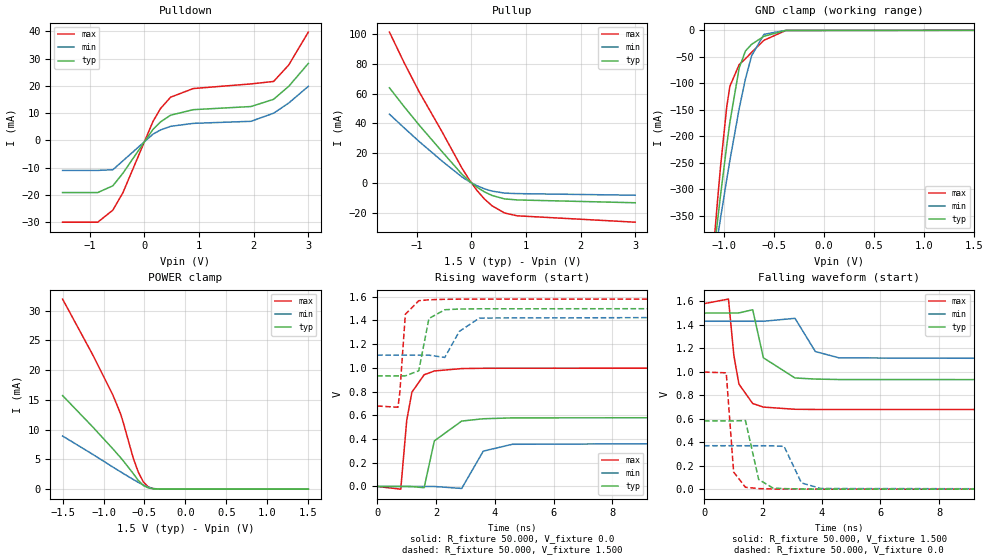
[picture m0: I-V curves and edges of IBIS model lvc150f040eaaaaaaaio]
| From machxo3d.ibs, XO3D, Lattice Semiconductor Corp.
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|   Model lvc150f040eaaaaaaaio
[Model] lvc150f040eaaaaaaaio
Model_type I/O
Polarity   Non-Inverting
Enable   Active-Low
Vinl =  0.375V
Vinh =  1.125V
Vmeas =  0.750V
Cref =  0.0F
Rref =  1.000M
Vref =  0.0V
C_comp   4.200pF   3.800pF   7.500pF
[Temperature Range]   25.000   0.105k   -40.000
[Voltage Range]   1.500V   1.430V   1.580V
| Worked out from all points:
|   slope of the pulldown table from 0 to 0.225 V, typ, clamps not added: 40.7 ohm
|   slope of the pullup table from 0 to 0.225 V, typ, clamps not added: 38.9 ohm
|   GND clamp passes 1 mA (typ) near -0.44 V on its own axis
|   POWER clamp passes 1 mA (typ) near -0.55 V on its own axis
|   rising waveform, R_fixture 50.000, V_fixture 0.0: 20-80 % time 418ps typ, 496ps min, 298ps max; typ from 0 V to 0.581 V
|   rising waveform, R_fixture 50.000, V_fixture 1.500: 20-80 % time 260ps typ, 435ps min, 140ps max; typ from 0.932 V to 1.5 V
|   falling waveform, R_fixture 50.000, V_fixture 1.500: 20-80 % time 377ps typ, 483ps min, 314ps max; typ from 1.5 V to 0.932 V
|   falling waveform, R_fixture 50.000, V_fixture 0.0: 20-80 % time 249ps typ, 395ps min, 149ps max; typ from 0.581 V to 0 V
[Pulldown]
|Voltage   I(typ)   I(min)   I(max)
-1.5V     -19.1mA    -10.99mA   -29.96mA
-856mV    -19.1mA    -10.99mA   -29.96mA
-580mV    -16.64mA   -10.73mA   -25.56mA
-396mV    -12.04mA   -7.496mA   -19.19mA
156mV     4.064mA    2.312mA    6.984mA
294mV     6.796mA    3.838mA    11.69mA
478mV     9.247mA    5.168mA    15.84mA
892mV     11.27mA    6.25mA     19.01mA
1.95V     12.42mA    7.008mA    20.71mA
2.364V    15.07mA    9.98mA     21.61mA
2.64V     19.8mA     13.69mA    27.61mA
3V        28.21mA    19.82mA    39.7mA
[Pullup]
|Voltage   I(typ)   I(min)   I(max)
-1.5V     64.05mA    46.27mA    101.6mA
-1.232V   51.39mA    37.09mA    81.04mA
-956mV    38.94mA    27.86mA    61.36mA
-542mV    21.27mA    14.84mA    34.76mA
-174mV    5.857mA    4.015mA    10.01mA
-36mV     1.123mA    756.4uA    1.958mA
102mV     -2.891mA   -1.927mA   -5.109mA
240mV     -6.098mA   -4.031mA   -10.91mA
378mV     -8.511mA   -5.568mA   -15.45mA
608mV     -10.83mA   -6.929mA   -20.32mA
838mV     -11.52mA   -7.262mA   -22.22mA
3V        -13.42mA   -8.343mA   -26.52mA
[GND_clamp]
|Voltage   I(typ)   I(min)   I(max)
-1.5V     -1.124A    -960.6mA   -1.411A
-1.097V   -411.6mA   -430.5mA   -392.9mA
-1.066V   -360.7mA   -392.1mA   -323mA
-1.035V   -311mA     -354.2mA   -256.7mA
-973mV    -216.8mA   -280.8mA   -144.2mA
-942mV    -173.4mA   -245.5mA   -105.6mA
-849mV    -71.05mA   -147.7mA   -64.59mA
-787mV    -39.16mA   -92.07mA   -53.68mA
-725mV    -26.4mA    -48.02mA   -41.58mA
-601mV    -11.15mA   -7.544mA   -18.72mA
-384mV    -236.4uA   -103.3uA   -351.1uA
1.5V      0A         0A         0A
[POWER_clamp]
|Voltage   I(typ)   I(min)   I(max)
-1.5V     15.72mA    8.929mA    31.93mA
-1.135V   10.5mA     5.879mA    22.65mA
-887mV    6.787mA    3.722mA    15.85mA
-794mV    5.333mA    2.928mA    12.72mA
-763mV    4.831mA    2.666mA    11.38mA
-639mV    2.654mA    1.642mA    5.303mA
-577mV    1.493mA    1.154mA    2.909mA
-515mV    627.3uA    700.9uA    1.235mA
-453mV    200.7uA    325.5uA    363.9uA
-391mV    56.19uA    99.29uA    82.51uA
-298mV    7.73uA     11.12uA    7.668uA
1.5V      0A         0A         4.131nA
[Ramp]
| variable   typ   min   max
dV/dt_r   0.349/0.408n   0.222/0.495n   0.598/0.299n
dV/dt_f   0.341/0.380n   0.194/0.491n   0.541/0.315n
R_load = 50.000
[Rising Waveform]
R_fixture= 50.000
V_fixture= 0.0
V_fixture_min= 0.0
V_fixture_max= 0.0
|time   V(typ)   V(min)   V(max)
0s        4.722nV    51.53nV    2.531nV
803ps     24.62uV    32.2uV     -22.65mV
1.006ns   180.6uV    7.206uV    557.2mV
1.182ns   -750.5uV   7.206uV    794.7mV
1.598ns   -10.39mV   97.67uV    941.8mV
1.946ns   384.7mV    92.19uV    973.8mV
2.876ns   551.5mV    -16.66mV   994mV
3.61ns    570.9mV    298mV      996.5mV
4.598ns   578.4mV    355.7mV    997mV
20ns      581.2mV    370.1mV    997.2mV
[Rising Waveform]
R_fixture= 50.000
V_fixture= 1.500
V_fixture_min= 1.430
V_fixture_max= 1.580
|time   V(typ)   V(min)   V(max)
0s        932.1mV    1.107V     678.4mV
707ps     932.1mV    1.107V     668.1mV
772ps     932mV      1.107V     794mV
959ps     932.4mV    1.107V     1.452V
1.416ns   975.6mV    1.107V     1.566V
1.761ns   1.416V     1.107V     1.574V
2.301ns   1.49V      1.088V     1.578V
2.797ns   1.496V     1.308V     1.579V
3.478ns   1.498V     1.42V      1.58V
20ns      1.5V       1.43V      1.58V
[Falling Waveform]
R_fixture= 50.000
V_fixture= 1.500
V_fixture_min= 1.430
V_fixture_max= 1.580
|time   V(typ)   V(min)   V(max)
0s        1.5V       1.43V      1.58V
832ps     1.5V       1.43V      1.619V
1.016ns   1.5V       1.43V      1.137V
1.188ns   1.501V     1.43V      894.6mV
1.656ns   1.528V     1.43V      729.6mV
2.019ns   1.119V     1.43V      699mV
3.096ns   946.9mV    1.455V     680.4mV
3.789ns   937.7mV    1.172V     678.8mV
4.6ns     933.7mV    1.118V     678.5mV
20ns      932.1mV    1.107V     678.4mV
[Falling Waveform]
R_fixture= 50.000
V_fixture= 0.0
V_fixture_min= 0.0
V_fixture_max= 0.0
|time   V(typ)   V(min)   V(max)
0s        581.2mV    370.1mV    997.2mV
756ps     581.3mV    370mV      990.8mV
1.007ns   581.3mV    370.2mV    146.1mV
1.41ns    584.3mV    370.1mV    16.06mV
1.86ns    82.34mV    370.1mV    4.92mV
2.344ns   9.921mV    369.5mV    1.276mV
2.725ns   4.587mV    364mV      488.2uV
3.316ns   1.707mV    53.46mV    153.7uV
3.979ns   590.3uV    5.627mV    43.77uV
20ns      -110.5nV   45.57nV    -214.2nV
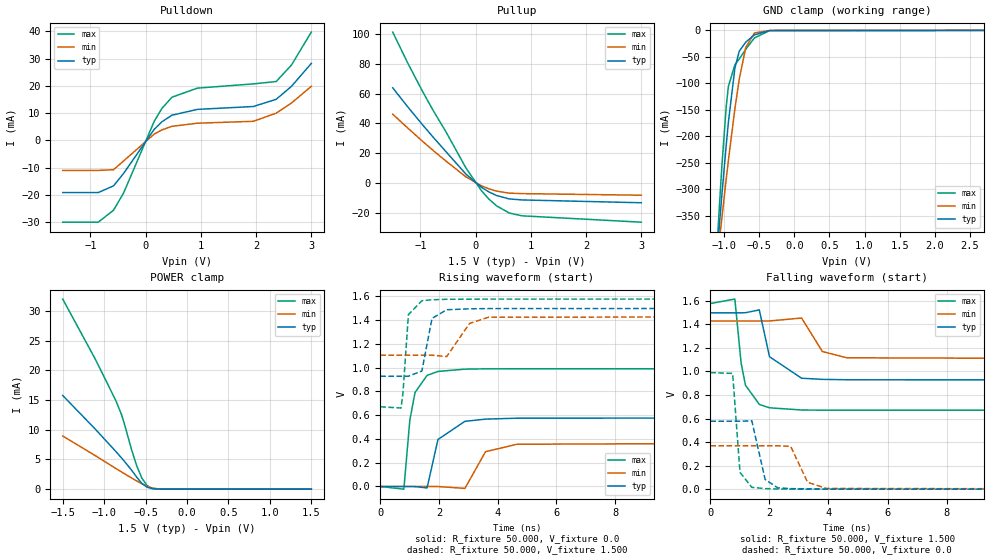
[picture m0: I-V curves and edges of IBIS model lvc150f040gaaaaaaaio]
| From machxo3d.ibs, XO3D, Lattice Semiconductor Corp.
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|   Model lvc150f040gaaaaaaaio
[Model] lvc150f040gaaaaaaaio
Model_type I/O
Polarity   Non-Inverting
Enable   Active-Low
Vinl =  0.375V
Vinh =  1.125V
Vmeas =  0.750V
Cref =  0.0F
Rref =  1.000M
Vref =  0.0V
C_comp   4.200pF   3.800pF   7.500pF
[Temperature Range]   25.000   0.105k   -40.000
[Voltage Range]   1.500V   1.430V   1.580V
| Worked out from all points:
|   slope of the pulldown table from 0 to 0.225 V, typ, clamps not added: 40.7 ohm
|   slope of the pullup table from 0 to 0.225 V, typ, clamps not added: 38.9 ohm
|   GND clamp passes 1 mA (typ) near -0.43 V on its own axis
|   POWER clamp passes 1 mA (typ) near -0.55 V on its own axis
|   rising waveform, R_fixture 50.000, V_fixture 0.0: 20-80 % time 404ps typ, 495ps min, 293ps max; typ from 0 V to 0.577 V
|   rising waveform, R_fixture 50.000, V_fixture 1.500: 20-80 % time 261ps typ, 437ps min, 140ps max; typ from 0.928 V to 1.5 V
|   falling waveform, R_fixture 50.000, V_fixture 1.500: 20-80 % time 371ps typ, 477ps min, 313ps max; typ from 1.5 V to 0.928 V
|   falling waveform, R_fixture 50.000, V_fixture 0.0: 20-80 % time 248ps typ, 398ps min, 147ps max; typ from 0.577 V to 0 V
[Pulldown]
|Voltage   I(typ)   I(min)   I(max)
-1.5V     -19.1mA    -10.99mA   -29.96mA
-856mV    -19.1mA    -10.99mA   -29.96mA
-580mV    -16.64mA   -10.73mA   -25.56mA
-396mV    -12.04mA   -7.496mA   -19.19mA
156mV     4.064mA    2.312mA    6.984mA
294mV     6.796mA    3.838mA    11.69mA
478mV     9.247mA    5.168mA    15.84mA
938mV     11.37mA    6.303mA    19.16mA
1.95V     12.42mA    7.008mA    20.71mA
2.364V    15.06mA    9.98mA     21.58mA
2.64V     19.8mA     13.69mA    27.6mA
3V        28.21mA    19.82mA    39.69mA
[Pullup]
|Voltage   I(typ)   I(min)   I(max)
-1.5V     64.05mA    46.27mA    101.6mA
-1.232V   51.39mA    37.09mA    81.04mA
-956mV    38.94mA    27.86mA    61.35mA
-772mV    30.95mA    21.95mA    49.04mA
-542mV    21.27mA    14.84mA    34.76mA
-174mV    5.857mA    4.015mA    10.01mA
102mV     -2.891mA   -1.927mA   -5.109mA
240mV     -6.098mA   -4.031mA   -10.91mA
378mV     -8.511mA   -5.568mA   -15.45mA
608mV     -10.83mA   -6.929mA   -20.32mA
838mV     -11.52mA   -7.262mA   -22.22mA
3V        -13.42mA   -8.343mA   -26.52mA
[GND_clamp]
|Voltage   I(typ)   I(min)   I(max)
-1.5V     -1.124A    -960.6mA   -1.411A
-1.097V   -411.6mA   -430.5mA   -393mA
-1.066V   -360.7mA   -392.1mA   -323mA
-1.035V   -311mA     -354.2mA   -256.8mA
-973mV    -216.9mA   -280.8mA   -144.3mA
-942mV    -173.5mA   -245.5mA   -105.7mA
-849mV    -71.09mA   -147.7mA   -64.66mA
-787mV    -39.21mA   -92.09mA   -53.75mA
-694mV    -22.05mA   -31.84mA   -35.55mA
-570mV    -8.285mA   -4.678mA   -14.06mA
-353mV    -178.3uA   -91.12uA   -279.1uA
3V        108.1uA    41.24uA    254.4uA
[POWER_clamp]
|Voltage   I(typ)   I(min)   I(max)
-1.5V     15.78mA    8.958mA    32.02mA
-1.104V   10.07mA    5.622mA    21.83mA
-856mV    6.305mA    3.46mA     14.84mA
-794mV    5.324mA    2.93mA     12.69mA
-763mV    4.82mA     2.667mA    11.36mA
-670mV    3.216mA    1.891mA    6.697mA
-608mV    2.042mA    1.391mA    3.973mA
-546mV    979.4uA    916.1uA    1.9mA
-484mV    340.1uA    494.4uA    627.5uA
-422mV    90.48uA    185.7uA    125.7uA
-329mV    10.53uA    21.57uA    6.907uA
1.5V      0A         0A         -3.95nA
[Ramp]
| variable   typ   min   max
dV/dt_r   0.346/0.404n   0.221/0.491n   0.594/0.299n
dV/dt_f   0.342/0.379n   0.194/0.491n   0.544/0.313n
R_load = 50.000
[Rising Waveform]
R_fixture= 50.000
V_fixture= 0.0
V_fixture_min= 0.0
V_fixture_max= 0.0
|time   V(typ)   V(min)   V(max)
0s        4.549nV    50.98nV    2.322nV
803ps     24.5uV     10.5uV     -22.57mV
1.006ns   180.9uV    10.5uV     555.7mV
1.183ns   -750.6uV   10.5uV     790.7mV
1.594ns   -12.6mV    101.6uV    934.7mV
1.965ns   395.4mV    -311.1uV   968mV
2.883ns   548.3mV    -16.12mV   987.3mV
3.586ns   566.7mV    292.8mV    989.9mV
4.658ns   574.7mV    355.5mV    990.5mV
20ns      577.2mV    368.8mV    990.6mV
[Rising Waveform]
R_fixture= 50.000
V_fixture= 1.500
V_fixture_min= 1.430
V_fixture_max= 1.580
|time   V(typ)   V(min)   V(max)
0s        927.7mV    1.105V     670.5mV
707ps     927.7mV    1.105V     660.3mV
774ps     927.6mV    1.105V     791.7mV
959ps     928mV      1.105V     1.446V
1.416ns   971.1mV    1.105V     1.563V
1.762ns   1.414V     1.105V     1.571V
2.262ns   1.487V     1.093V     1.575V
3.041ns   1.495V     1.372V     1.576V
3.686ns   1.497V     1.424V     1.577V
20ns      1.498V     1.429V     1.577V
[Falling Waveform]
R_fixture= 50.000
V_fixture= 1.500
V_fixture_min= 1.430
V_fixture_max= 1.580
|time   V(typ)   V(min)   V(max)
0s        1.498V     1.429V     1.577V
832ps     1.498V     1.429V     1.615V
1.044ns   1.498V     1.429V     1.071V
1.191ns   1.499V     1.429V     883.1mV
1.659ns   1.523V     1.429V     720.4mV
2.005ns   1.125V     1.429V     691.3mV
3.091ns   942.5mV    1.454V     672.6mV
3.795ns   932.8mV    1.169V     671mV
4.628ns   929.3mV    1.116V     670.6mV
20ns      927.7mV    1.105V     670.5mV
[Falling Waveform]
R_fixture= 50.000
V_fixture= 0.0
V_fixture_min= 0.0
V_fixture_max= 0.0
|time   V(typ)   V(min)   V(max)
0s        577.2mV    368.8mV    990.6mV
757ps     577.3mV    368.8mV    983.3mV
1.006ns   577.3mV    368.8mV    142.7mV
1.406ns   580.4mV    368.8mV    15.63mV
1.857ns   82.11mV    368.8mV    4.757mV
2.287ns   11.12mV    368.4mV    1.438mV
2.721ns   4.729mV    363.6mV    590.4uV
3.294ns   1.781mV    58.4mV     129.7uV
3.938ns   631.9uV    6.034mV    71.45uV
20ns      -288.2nV   10.71nV    -37.41nV
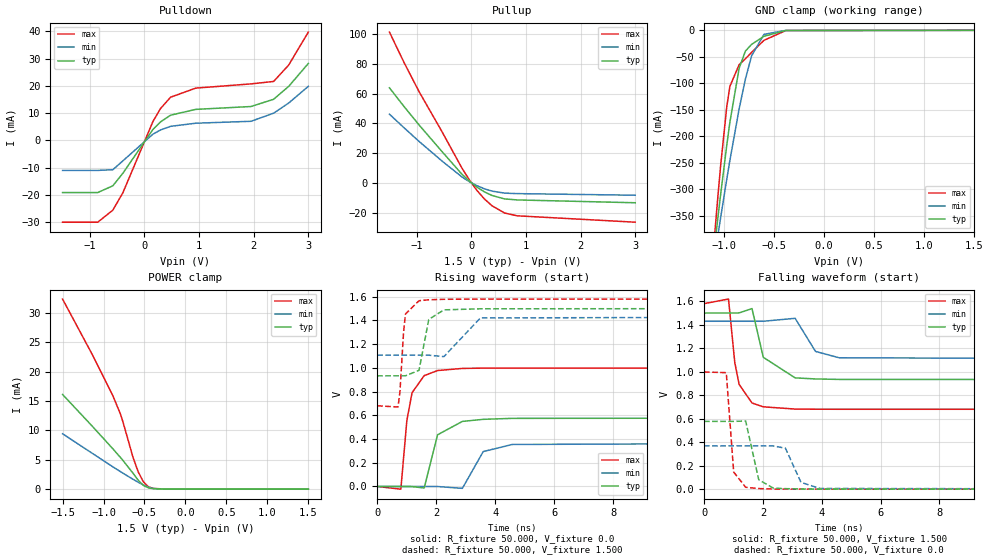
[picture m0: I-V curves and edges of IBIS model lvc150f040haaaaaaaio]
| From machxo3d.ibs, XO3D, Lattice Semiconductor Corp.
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|   Model lvc150f040haaaaaaaio
[Model] lvc150f040haaaaaaaio
Model_type I/O
Polarity   Non-Inverting
Enable   Active-Low
Vinl =  0.375V
Vinh =  1.125V
Vmeas =  0.750V
Cref =  0.0F
Rref =  1.000M
Vref =  0.0V
C_comp   4.200pF   3.800pF   7.500pF
[Temperature Range]   25.000   0.105k   -40.000
[Voltage Range]   1.500V   1.430V   1.580V
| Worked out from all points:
|   slope of the pulldown table from 0 to 0.225 V, typ, clamps not added: 40.7 ohm
|   slope of the pullup table from 0 to 0.225 V, typ, clamps not added: 38.9 ohm
|   GND clamp passes 1 mA (typ) near -0.43 V on its own axis
|   POWER clamp passes 1 mA (typ) near -0.54 V on its own axis
|   rising waveform, R_fixture 50.000, V_fixture 0.0: 20-80 % time 403ps typ, 493ps min, 303ps max; typ from 0 V to 0.577 V
|   rising waveform, R_fixture 50.000, V_fixture 1.500: 20-80 % time 260ps typ, 436ps min, 140ps max; typ from 0.933 V to 1.5 V
|   falling waveform, R_fixture 50.000, V_fixture 1.500: 20-80 % time 378ps typ, 482ps min, 315ps max; typ from 1.5 V to 0.933 V
|   falling waveform, R_fixture 50.000, V_fixture 0.0: 20-80 % time 249ps typ, 398ps min, 149ps max; typ from 0.577 V to 0 V
[Pulldown]
|Voltage   I(typ)   I(min)   I(max)
-1.5V     -19.1mA    -10.99mA   -29.96mA
-856mV    -19.1mA    -10.99mA   -29.96mA
-580mV    -16.64mA   -10.73mA   -25.56mA
-396mV    -12.04mA   -7.496mA   -19.19mA
156mV     4.064mA    2.312mA    6.984mA
294mV     6.796mA    3.838mA    11.69mA
478mV     9.247mA    5.168mA    15.84mA
938mV     11.37mA    6.303mA    19.16mA
1.95V     12.42mA    7.008mA    20.71mA
2.364V    15.07mA    9.98mA     21.6mA
2.64V     19.79mA    13.69mA    27.6mA
3V        28.2mA     19.82mA    39.69mA
[Pullup]
|Voltage   I(typ)   I(min)   I(max)
-1.5V     64.05mA    46.28mA    101.6mA
-1.232V   51.39mA    37.09mA    81.04mA
-956mV    38.94mA    27.87mA    61.36mA
-542mV    21.27mA    14.84mA    34.76mA
-174mV    5.857mA    4.015mA    10.01mA
-36mV     1.123mA    756.4uA    1.958mA
102mV     -2.891mA   -1.927mA   -5.109mA
240mV     -6.098mA   -4.031mA   -10.91mA
378mV     -8.511mA   -5.568mA   -15.45mA
608mV     -10.83mA   -6.929mA   -20.32mA
838mV     -11.52mA   -7.262mA   -22.22mA
3V        -13.42mA   -8.343mA   -26.52mA
[GND_clamp]
|Voltage   I(typ)   I(min)   I(max)
-1.5V     -1.124A    -960.6mA   -1.411A
-1.097V   -411.6mA   -430.5mA   -393mA
-1.066V   -360.7mA   -392.1mA   -323mA
-1.035V   -311mA     -354.2mA   -256.8mA
-973mV    -216.9mA   -280.8mA   -144.3mA
-942mV    -173.5mA   -245.5mA   -105.7mA
-849mV    -71.09mA   -147.7mA   -64.66mA
-787mV    -39.21mA   -92.09mA   -53.75mA
-725mV    -26.45mA   -48.04mA   -41.65mA
-601mV    -11.21mA   -7.588mA   -18.81mA
-384mV    -319.8uA   -151.2uA   -484.4uA
1.5V      -41.68nA   0A         -8.283uA
[POWER_clamp]
|Voltage   I(typ)   I(min)   I(max)
-1.5V     16.13mA    9.435mA    32.38mA
-1.135V   10.69mA    6.084mA    22.87mA
-887mV    6.888mA    3.813mA    15.95mA
-794mV    5.406mA    2.992mA    12.8mA
-763mV    4.897mA    2.724mA    11.46mA
-639mV    2.697mA    1.677mA    5.367mA
-577mV    1.529mA    1.181mA    2.962mA
-515mV    656.7uA    722.8uA    1.279mA
-453mV    227.4uA    343.3uA    403.8uA
-391mV    80.76uA    114.4uA    122.7uA
-267mV    21.1uA     15.5uA     34.42uA
1.5V      0A         0A         0A
[Ramp]
| variable   typ   min   max
dV/dt_r   0.346/0.404n   0.221/0.491n   0.599/0.307n
dV/dt_f   0.340/0.381n   0.194/0.491n   0.540/0.316n
R_load = 50.000
[Rising Waveform]
R_fixture= 50.000
V_fixture= 0.0
V_fixture_min= 0.0
V_fixture_max= 0.0
|time   V(typ)   V(min)   V(max)
0s        4.549nV    50.98nV    2.322nV
803ps     24.58uV    32.13uV    -22.57mV
1.006ns   180.8uV    7.133uV    555.7mV
1.183ns   -750.5uV   7.133uV    790.7mV
1.594ns   -12.6mV    97.51uV    934.7mV
2.047ns   435.9mV    -314.1uV   977.4mV
2.888ns   548.6mV    -15.7mV    995.3mV
3.594ns   566.1mV    294.3mV    997.8mV
4.58ns    574.4mV    354.3mV    998.3mV
20ns      577.2mV    368.8mV    998.4mV
[Rising Waveform]
R_fixture= 50.000
V_fixture= 1.500
V_fixture_min= 1.430
V_fixture_max= 1.580
|time   V(typ)   V(min)   V(max)
0s        933mV      1.107V     680.4mV
707ps     933.1mV    1.107V     670.1mV
772ps     933mV      1.107V     796.1mV
896ps     933mV      1.107V     1.304V
960ps     933.3mV    1.107V     1.454V
1.418ns   979.1mV    1.107V     1.566V
1.749ns   1.408V     1.107V     1.574V
2.262ns   1.489V     1.095V     1.578V
3.499ns   1.498V     1.421V     1.58V
20ns      1.5V       1.43V      1.58V
[Falling Waveform]
R_fixture= 50.000
V_fixture= 1.500
V_fixture_min= 1.430
V_fixture_max= 1.580
|time   V(typ)   V(min)   V(max)
0s        1.5V       1.43V      1.58V
832ps     1.5V       1.43V      1.619V
1.045ns   1.5V       1.43V      1.079V
1.193ns   1.501V     1.43V      892.3mV
1.63ns    1.538V     1.43V      733.9mV
2.014ns   1.123V     1.43V      701.3mV
3.096ns   947.9mV    1.455V     682.2mV
3.789ns   938.7mV    1.173V     680.8mV
4.594ns   934.7mV    1.119V     680.5mV
20ns      933mV      1.107V     680.4mV
[Falling Waveform]
R_fixture= 50.000
V_fixture= 0.0
V_fixture_min= 0.0
V_fixture_max= 0.0
|time   V(typ)   V(min)   V(max)
0s        577.2mV    368.8mV    998.4mV
756ps     577.3mV    368.7mV    992mV
1.008ns   577.3mV    368.8mV    146.1mV
1.415ns   580.1mV    368.8mV    16.1mV
1.86ns    80.4mV     368.8mV    5.099mV
2.348ns   9.485mV    368.2mV    1.35mV
2.766ns   4.302mV    348.9mV    537.6uV
3.294ns   1.781mV    58.4mV     179.7uV
3.938ns   631.9uV    6.034mV    55.71uV
20ns      -288.2nV   -40nV      -696.6nV
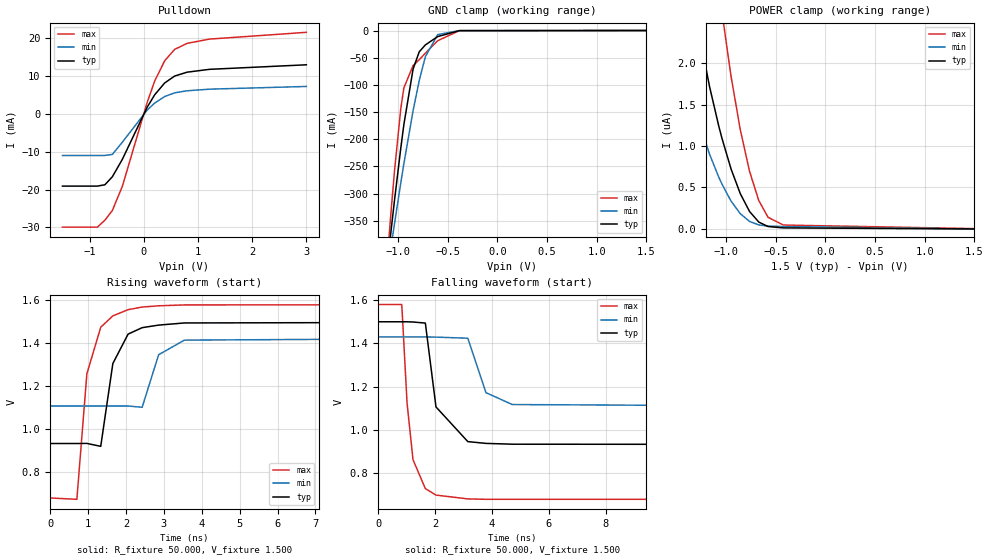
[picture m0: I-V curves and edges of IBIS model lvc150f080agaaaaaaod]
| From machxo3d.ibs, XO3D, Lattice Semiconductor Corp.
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|   Model lvc150f080agaaaaaaod
[Model] lvc150f080agaaaaaaod
Model_type I/O_open_drain
Polarity   Non-Inverting
Enable   Active-Low
Vinl =  0.375V
Vinh =  1.125V
Vmeas =  0.750V
Cref =  0.0F
Rref = 10.00k
Vref = 1.50V
C_comp   4.200pF   3.800pF   7.500pF
[Temperature Range]   25.000   0.105k   -40.000
[Voltage Range]   1.500V   1.430V   1.580V
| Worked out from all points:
|   slope of the pulldown table from 0 to 0.225 V, typ, clamps not added: 40.7 ohm
|   GND clamp passes 1 mA (typ) near -0.44 V on its own axis
|   rising waveform, R_fixture 50.000, V_fixture 1.500: 20-80 % time 354ps typ, 376ps min, 352ps max; typ from 0.932 V to 1.5 V
|   falling waveform, R_fixture 50.000, V_fixture 1.500: 20-80 % time 393ps typ, 494ps min, 317ps max; typ from 1.5 V to 0.932 V
[Pulldown]
|Voltage   I(typ)   I(min)   I(max)
-1.5V     -19.1mA    -10.99mA   -29.96mA
-856mV    -19.1mA    -10.99mA   -29.96mA
-718mV    -18.75mA   -10.99mA   -28.13mA
-580mV    -16.64mA   -10.73mA   -25.56mA
-396mV    -12.04mA   -7.496mA   -19.19mA
64mV      1.796mA    1.025mA    3.085mA
202mV     5.062mA    2.873mA    8.703mA
386mV     8.187mA    4.599mA    14.06mA
570mV     10.01mA    5.571mA    17.07mA
800mV     11.04mA    6.122mA    18.66mA
1.214V    11.79mA    6.545mA    19.79mA
3V        12.99mA    7.26mA     21.58mA
[GND_clamp]
|Voltage   I(typ)   I(min)   I(max)
-1.5V     -1.124A    -960.6mA   -1.411A
-1.097V   -411.6mA   -430.5mA   -392.9mA
-1.066V   -360.7mA   -392.1mA   -323mA
-1.035V   -311mA     -354.2mA   -256.8mA
-973mV    -216.9mA   -280.8mA   -144.3mA
-942mV    -173.5mA   -245.5mA   -105.7mA
-849mV    -71.07mA   -147.7mA   -64.62mA
-787mV    -39.18mA   -92.07mA   -53.7mA
-725mV    -26.42mA   -48.02mA   -41.6mA
-601mV    -11.16mA   -7.547mA   -18.74mA
-384mV    -237.5uA   -103.4uA   -356uA
1.5V      0A         0A         0A
[POWER_clamp]
|Voltage   I(typ)   I(min)   I(max)
-1.5V     4.017uA    2.297uA    8.486uA
-1.321V   2.676uA    1.475uA    5.815uA
-1.166V   1.719uA    902.9nA    3.892uA
-1.073V   1.242uA    625.4nA    2.92uA
-1.042V   1.099uA    544.2nA    2.626uA
-949mV    723.1nA    335.9nA    1.84uA
-856mV    425.5nA    184nA      1.196uA
-763mV    211.1nA    90.94nA    695.5nA
-670mV    83.02nA    48.42nA    343nA
-577mV    29.37nA    34.61nA    141nA
-422mV    12.82nA    29.5nA     47.26nA
1.5V      0A         0A         4.136nA
[Ramp]
| variable   typ   min   max
dV/dt_r   0.341/0.351n   0.194/0.377n   0.541/0.352n
dV/dt_f   0.341/0.393n   0.194/0.502n   0.541/0.313n
R_load = 50.000
[Rising Waveform]
R_fixture= 50.000
V_fixture= 1.500
V_fixture_min= 1.430
V_fixture_max= 1.580
|time   V(typ)   V(min)   V(max)
0s        932.1mV    1.107V     678.4mV
702ps     932.1mV    1.107V     672mV
966ps     932.6mV    1.107V     1.257V
1.332ns   919mV      1.107V     1.474V
1.652ns   1.305V     1.107V     1.527V
2.054ns   1.442V     1.107V     1.556V
2.425ns   1.472V     1.101V     1.568V
2.861ns   1.484V     1.346V     1.574V
3.541ns   1.494V     1.414V     1.578V
20ns      1.5V       1.43V      1.58V
[Falling Waveform]
R_fixture= 50.000
V_fixture= 1.500
V_fixture_min= 1.430
V_fixture_max= 1.580
|time   V(typ)   V(min)   V(max)
0s        1.5V       1.43V      1.58V
829ps     1.5V       1.43V      1.58V
1.015ns   1.5V       1.43V      1.124V
1.224ns   1.499V     1.43V      861.8mV
1.658ns   1.494V     1.43V      728mV
2.032ns   1.106V     1.429V     698mV
3.151ns   945.5mV    1.424V     680.4mV
3.789ns   937.3mV    1.172V     678.5mV
4.716ns   933.5mV    1.117V     678.6mV
20ns      932.1mV    1.107V     678.4mV
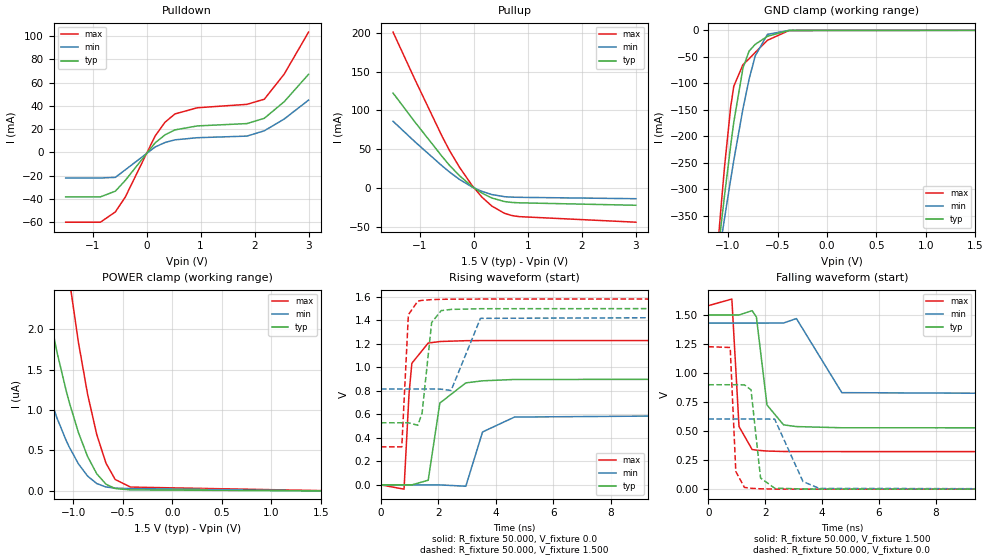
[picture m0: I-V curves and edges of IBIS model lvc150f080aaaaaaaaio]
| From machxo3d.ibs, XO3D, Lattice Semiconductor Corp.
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|   Model lvc150f080aaaaaaaaio
[Model] lvc150f080aaaaaaaaio
Model_type I/O
Polarity   Non-Inverting
Enable   Active-Low
Vinl =  0.375V
Vinh =  1.125V
Vmeas =  0.750V
Cref =  0.0F
Rref =  1.000M
Vref =  0.0V
C_comp   4.200pF   3.800pF   7.500pF
[Temperature Range]   25.000   0.105k   -40.000
[Voltage Range]   1.500V   1.430V   1.580V
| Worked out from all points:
|   slope of the pulldown table from 0 to 0.225 V, typ, clamps not added: 20.4 ohm
|   slope of the pullup table from 0 to 0.225 V, typ, clamps not added: 23.3 ohm
|   GND clamp passes 1 mA (typ) near -0.44 V on its own axis
|   rising waveform, R_fixture 50.000, V_fixture 0.0: 20-80 % time 388ps typ, 514ps min, 171ps max; typ from 0 V to 0.899 V
|   rising waveform, R_fixture 50.000, V_fixture 1.500: 20-80 % time 239ps typ, 413ps min, 114ps max; typ from 0.528 V to 1.5 V
|   falling waveform, R_fixture 50.000, V_fixture 1.500: 20-80 % time 302ps typ, 470ps min, 166ps max; typ from 1.5 V to 0.528 V
|   falling waveform, R_fixture 50.000, V_fixture 0.0: 20-80 % time 212ps typ, 373ps min, 105ps max; typ from 0.899 V to 0 V
[Pulldown]
|Voltage   I(typ)   I(min)   I(max)
-1.5V     -38.2mA    -21.99mA   -59.93mA
-856mV    -38.2mA    -21.99mA   -59.93mA
-580mV    -33.29mA   -21.45mA   -51.12mA
-396mV    -24.09mA   -14.99mA   -38.38mA
156mV     8.127mA    4.623mA    13.97mA
340mV     15.07mA    8.487mA    25.9mA
524mV     19.32mA    10.78mA    33.03mA
938mV     22.73mA    12.61mA    38.32mA
1.858V    24.74mA    13.99mA    41.25mA
2.18V     29.28mA    18.55mA    45.66mA
2.548V    43.52mA    28.65mA    67.2mA
3V        67.05mA    44.93mA    103.3mA
[Pullup]
|Voltage   I(typ)   I(min)   I(max)
-1.5V     122.5mA    86.09mA    201.2mA
-1.094V   85.05mA    59.58mA    139.9mA
-588mV    40.38mA    28.31mA    66.15mA
-450mV    28.89mA    20.36mA    47.84mA
-266mV    15.63mA    10.83mA    26.41mA
-36mV     1.872mA    1.261mA    3.264mA
148mV     -6.75mA    -4.487mA   -11.97mA
332mV     -12.99mA   -8.529mA   -23.46mA
562mV     -17.55mA   -11.28mA   -32.68mA
700mV     -18.72mA   -11.87mA   -35.61mA
838mV     -19.2mA    -12.1mA    -37.04mA
3V        -22.36mA   -13.9mA    -44.21mA
[GND_clamp]
|Voltage   I(typ)   I(min)   I(max)
-1.5V     -1.124A    -960.6mA   -1.411A
-1.097V   -411.6mA   -430.5mA   -392.9mA
-1.066V   -360.7mA   -392.1mA   -323mA
-1.035V   -311mA     -354.2mA   -256.7mA
-973mV    -216.8mA   -280.8mA   -144.2mA
-942mV    -173.4mA   -245.5mA   -105.6mA
-849mV    -71.05mA   -147.7mA   -64.59mA
-787mV    -39.16mA   -92.07mA   -53.68mA
-725mV    -26.4mA    -48.02mA   -41.58mA
-601mV    -11.15mA   -7.544mA   -18.72mA
-384mV    -236.4uA   -103.3uA   -351.1uA
1.5V      0A         0A         0A
[POWER_clamp]
|Voltage   I(typ)   I(min)   I(max)
-1.5V     4.017uA    2.297uA    8.486uA
-1.321V   2.676uA    1.475uA    5.815uA
-1.166V   1.719uA    902.9nA    3.892uA
-1.073V   1.242uA    625.4nA    2.92uA
-1.042V   1.099uA    544.2nA    2.626uA
-949mV    723.1nA    335.9nA    1.84uA
-856mV    425.6nA    184nA      1.196uA
-763mV    211.2nA    90.94nA    695.6nA
-670mV    83.05nA    48.41nA    343.1nA
-577mV    29.4nA     34.61nA    141.1nA
-422mV    12.85nA    29.5nA     47.32nA
1.5V      0A         0A         4.131nA
[Ramp]
| variable   typ   min   max
dV/dt_r   0.540/0.379n   0.363/0.518n   0.736/0.171n
dV/dt_f   0.583/0.303n   0.369/0.470n   0.754/0.166n
R_load = 50.000
[Rising Waveform]
R_fixture= 50.000
V_fixture= 0.0
V_fixture_min= 0.0
V_fixture_max= 0.0
|time   V(typ)   V(min)   V(max)
0s        2.959nV    35.35nV    1.474nV
805ps     20.68uV    3.785uV    -36.58mV
978ps     75.17uV    3.785uV    770.1mV
1.077ns   -196.1uV   3.785uV    1.034V
1.646ns   39.58mV    137.2uV    1.206V
2.05ns    695.2mV    -407.8uV   1.219V
2.954ns   867.2mV    -11.52mV   1.226V
3.537ns   884.8mV    450mV      1.227V
4.647ns   896.2mV    576.5mV    1.227V
20ns      899.2mV    604.4mV    1.227V
[Rising Waveform]
R_fixture= 50.000
V_fixture= 1.500
V_fixture_min= 1.430
V_fixture_max= 1.580
|time   V(typ)   V(min)   V(max)
0s        527.9mV    815.2mV    323.4mV
727ps     527.8mV    815.3mV    323.5mV
957ps     528.1mV    815.2mV    1.447V
1.285ns   506.5mV    815.1mV    1.563V
1.432ns   608.1mV    814.9mV    1.569V
1.766ns   1.381V     815.9mV    1.575V
2.098ns   1.482V     813.5mV    1.578V
2.443ns   1.492V     803mV      1.579V
3.464ns   1.498V     1.416V     1.58V
20ns      1.5V       1.43V      1.58V
[Falling Waveform]
R_fixture= 50.000
V_fixture= 1.500
V_fixture_min= 1.430
V_fixture_max= 1.580
|time   V(typ)   V(min)   V(max)
0s        1.5V       1.43V      1.58V
830ps     1.5V       1.43V      1.637V
1.082ns   1.5V       1.43V      539.7mV
1.542ns   1.537V     1.43V      341.5mV
1.693ns   1.483V     1.43V      335.5mV
2.065ns   725.1mV    1.43V      328.4mV
2.648ns   553.7mV    1.431V     324.3mV
3.1ns     538.9mV    1.469V     323.7mV
4.696ns   528.7mV    831.1mV    323.5mV
20ns      527.7mV    815.2mV    323.4mV
[Falling Waveform]
R_fixture= 50.000
V_fixture= 0.0
V_fixture_min= 0.0
V_fixture_max= 0.0
|time   V(typ)   V(min)   V(max)
0s        899.2mV    604.4mV    1.227V
772ps     899.2mV    604.4mV    1.22V
969ps     899.2mV    604.4mV    152.2mV
1.272ns   898.2mV    604.4mV    15.23mV
1.504ns   855.6mV    604.4mV    7.46mV
1.839ns   96.16mV    604.4mV    3.113mV
2.335ns   8.434mV    602.9mV    799.6uV
3.331ns   1.641mV    65.67mV    75.36uV
3.904ns   556.1uV    6.479mV    34.85uV
20ns      -297.8nV   -32.22nV   -526.2nV
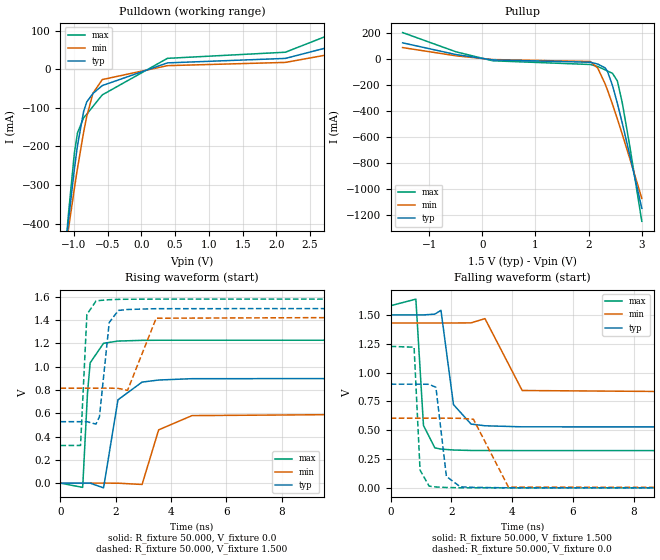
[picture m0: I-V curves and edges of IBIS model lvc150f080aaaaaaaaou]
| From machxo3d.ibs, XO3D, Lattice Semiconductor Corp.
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|   Model lvc150f080aaaaaaaaou
[Model] lvc150f080aaaaaaaaou
Model_type Output
Polarity   Non-Inverting
Enable   Active-High
Vmeas =  0.750V
Cref =  0.0F
Rref =  1.000M
Vref =  0.0V
C_comp   4.200pF   3.800pF   7.500pF
[Temperature Range]   25.000   0.105k   -40.000
[Voltage Range]   1.500V   1.430V   1.580V
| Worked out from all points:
|   slope of the pulldown table from 0 to 0.225 V, typ, clamps not added: 20.4 ohm
|   slope of the pullup table from 0 to 0.225 V, typ, clamps not added: 23.3 ohm
|   rising waveform, R_fixture 50.000, V_fixture 0.0: 20-80 % time 381ps typ, 516ps min, 170ps max; typ from 0 V to 0.899 V
|   rising waveform, R_fixture 50.000, V_fixture 1.500: 20-80 % time 239ps typ, 413ps min, 114ps max; typ from 0.528 V to 1.5 V
|   falling waveform, R_fixture 50.000, V_fixture 1.500: 20-80 % time 301ps typ, 467ps min, 166ps max; typ from 1.5 V to 0.528 V
|   falling waveform, R_fixture 50.000, V_fixture 0.0: 20-80 % time 212ps typ, 375ps min, 105ps max; typ from 0.899 V to 0 V
[Pulldown]
|Voltage   I(typ)   I(min)   I(max)
-1.5V     -1.126A    -962mA     -1.414A
-1.132V   -475.7mA   -477.5mA   -486mA
-1.086V   -400.2mA   -420.1mA   -383.6mA
-994mV    -259.5mA   -309.7mA   -217.9mA
-948mV    -198.4mA   -257.5mA   -165.3mA
-856mV    -109.3mA   -162.8mA   -125.9mA
-810mV    -84.86mA   -122.4mA   -116.6mA
-718mV    -62.87mA   -62.28mA   -96.47mA
-580mV    -42.42mA   -26.88mA   -66.58mA
386mV     16.37mA    9.198mA    28.13mA
2.134V    27.94mA    17.58mA    44.01mA
3V        67.06mA    44.93mA    103.3mA
[Pullup]
|Voltage   I(typ)   I(min)   I(max)
-1.5V     122.5mA    86.09mA    201.2mA
-496mV    32.56mA    22.97mA    53.7mA
194mV     -8.531mA   -5.655mA   -15.19mA
2.034V    -26.4mA    -21.05mA   -43.62mA
2.172V    -40.46mA   -72.01mA   -59.08mA
2.31V     -69.15mA   -192.2mA   -84.81mA
2.356V    -98.37mA   -241.2mA   -93.99mA
2.448V    -203.4mA   -347.3mA   -111mA
2.54V     -340.8mA   -460.5mA   -169.2mA
2.632V    -492.2mA   -577.9mA   -335.7mA
2.77V     -731.7mA   -759.3mA   -659.4mA
3V        -1.146A    -1.07A     -1.246A
[Ramp]
| variable   typ   min   max
dV/dt_r   0.540/0.376n   0.363/0.519n   0.736/0.170n
dV/dt_f   0.583/0.302n   0.369/0.469n   0.754/0.166n
R_load = 50.000
[Rising Waveform]
R_fixture= 50.000
V_fixture= 0.0
V_fixture_min= 0.0
V_fixture_max= 0.0
|time   V(typ)   V(min)   V(max)
0s        2.932nV    35.47nV    1.446nV
805ps     20.09uV    27.6uV     -36.64mV
978ps     101.8uV    2.604uV    771.2mV
1.075ns   -138.4uV   2.604uV    1.033V
1.56ns    -40.61mV   88.66uV    1.201V
2.081ns   715.4mV    -432.1uV   1.22V
2.954ns   867.6mV    -11.59mV   1.226V
3.554ns   885.4mV    457.3mV    1.227V
4.761ns   896.9mV    579.8mV    1.227V
20ns      899.2mV    604.4mV    1.227V
[Rising Waveform]
R_fixture= 50.000
V_fixture= 1.500
V_fixture_min= 1.430
V_fixture_max= 1.580
|time   V(typ)   V(min)   V(max)
0s        527.9mV    815.2mV    323.4mV
727ps     527.8mV    815.2mV    323.5mV
957ps     528.1mV    815.2mV    1.448V
1.285ns   506.5mV    815.1mV    1.563V
1.412ns   571.3mV    815.1mV    1.568V
1.764ns   1.379V     815.8mV    1.575V
2.098ns   1.483V     813.5mV    1.578V
2.428ns   1.491V     796.5mV    1.579V
3.464ns   1.498V     1.416V     1.58V
20ns      1.5V       1.43V      1.58V
[Falling Waveform]
R_fixture= 50.000
V_fixture= 1.500
V_fixture_min= 1.430
V_fixture_max= 1.580
|time   V(typ)   V(min)   V(max)
0s        1.5V       1.43V      1.58V
830ps     1.5V       1.43V      1.637V
1.081ns   1.5V       1.43V      541.1mV
1.455ns   1.507V     1.43V      346.7mV
1.656ns   1.54V      1.43V      336.4mV
2.068ns   721.9mV    1.43V      328.2mV
2.646ns   553.4mV    1.431V     324.3mV
3.104ns   538.5mV    1.468V     323.8mV
4.329ns   529.3mV    844.4mV    323.4mV
20ns      527.7mV    815.2mV    323.4mV
[Falling Waveform]
R_fixture= 50.000
V_fixture= 0.0
V_fixture_min= 0.0
V_fixture_max= 0.0
|time   V(typ)   V(min)   V(max)
0s        899.2mV    604.4mV    1.227V
772ps     899.2mV    604.4mV    1.22V
968ps     899.2mV    604.4mV    154.4mV
1.264ns   898.3mV    604.4mV    15.09mV
1.49ns    872.2mV    604.4mV    7.643mV
1.835ns   99.73mV    604.4mV    3.057mV
2.292ns   8.96mV     603.2mV    964.6uV
2.725ns   4.309mV    594.9mV    310.1uV
3.877ns   585.5uV    6.446mV    28.65uV
20ns      -93.51nV   -227.1nV   -26.06nV
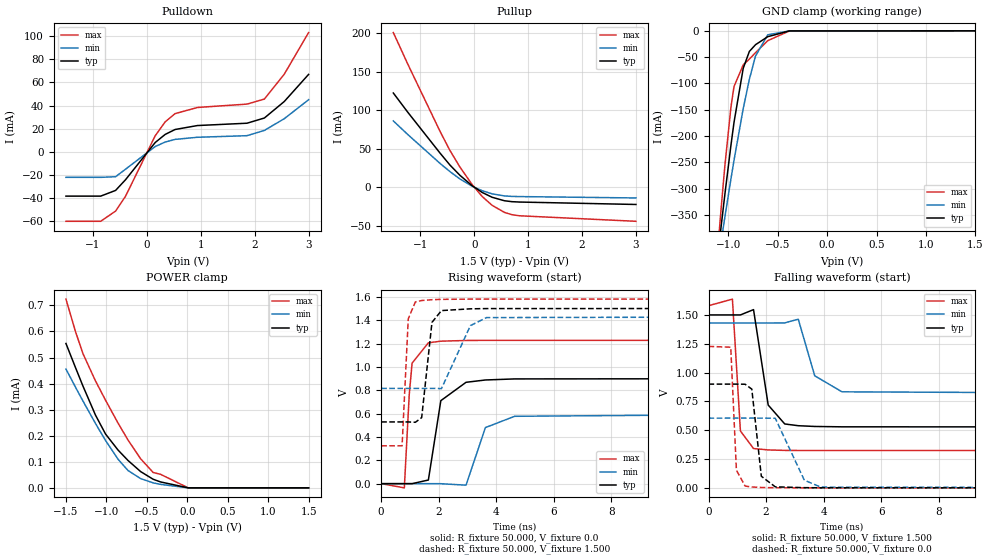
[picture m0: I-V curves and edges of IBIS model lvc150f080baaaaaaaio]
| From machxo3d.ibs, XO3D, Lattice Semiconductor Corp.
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|   Model lvc150f080baaaaaaaio
[Model] lvc150f080baaaaaaaio
Model_type I/O
Polarity   Non-Inverting
Enable   Active-Low
Vinl =  0.375V
Vinh =  1.125V
Vmeas =  0.750V
Cref =  0.0F
Rref =  1.000M
Vref =  0.0V
C_comp   4.200pF   3.800pF   7.500pF
[Temperature Range]   25.000   0.105k   -40.000
[Voltage Range]   1.500V   1.430V   1.580V
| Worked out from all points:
|   slope of the pulldown table from 0 to 0.225 V, typ, clamps not added: 20.4 ohm
|   slope of the pullup table from 0 to 0.225 V, typ, clamps not added: 23.3 ohm
|   GND clamp passes 1 mA (typ) near -0.44 V on its own axis
|   rising waveform, R_fixture 50.000, V_fixture 0.0: 20-80 % time 383ps typ, 523ps min, 170ps max; typ from 0 V to 0.9 V
|   rising waveform, R_fixture 50.000, V_fixture 1.500: 20-80 % time 239ps typ, 413ps min, 114ps max; typ from 0.529 V to 1.5 V
|   falling waveform, R_fixture 50.000, V_fixture 1.500: 20-80 % time 303ps typ, 470ps min, 166ps max; typ from 1.5 V to 0.528 V
|   falling waveform, R_fixture 50.000, V_fixture 0.0: 20-80 % time 212ps typ, 376ps min, 105ps max; typ from 0.9 V to 0 V
[Pulldown]
|Voltage   I(typ)   I(min)   I(max)
-1.5V     -38.2mA    -21.99mA   -59.93mA
-856mV    -38.2mA    -21.99mA   -59.93mA
-580mV    -33.29mA   -21.45mA   -51.12mA
-396mV    -24.09mA   -14.99mA   -38.38mA
156mV     8.127mA    4.623mA    13.97mA
340mV     15.07mA    8.487mA    25.9mA
524mV     19.32mA    10.78mA    33.03mA
938mV     22.73mA    12.61mA    38.32mA
1.858V    24.74mA    13.98mA    41.25mA
2.18V     29.24mA    18.53mA    45.59mA
2.548V    43.44mA    28.61mA    67.01mA
3V        66.89mA    45.03mA    103mA
[Pullup]
|Voltage   I(typ)   I(min)   I(max)
-1.5V     122.4mA    86.16mA    200.9mA
-1.232V   97.47mA    68.53mA    160mA
-634mV    44.41mA    31.02mA    72.65mA
-450mV    28.88mA    20.36mA    47.82mA
-266mV    15.63mA    10.83mA    26.41mA
-36mV     1.872mA    1.261mA    3.264mA
148mV     -6.75mA    -4.487mA   -11.97mA
332mV     -12.99mA   -8.529mA   -23.46mA
562mV     -17.55mA   -11.28mA   -32.68mA
700mV     -18.72mA   -11.87mA   -35.61mA
838mV     -19.2mA    -12.1mA    -37.04mA
3V        -22.36mA   -13.9mA    -44.21mA
[GND_clamp]
|Voltage   I(typ)   I(min)   I(max)
-1.5V     -1.124A    -960.6mA   -1.411A
-1.097V   -411.6mA   -430.5mA   -392.9mA
-1.066V   -360.7mA   -392.1mA   -323mA
-1.035V   -311mA     -354.2mA   -256.7mA
-973mV    -216.8mA   -280.8mA   -144.3mA
-942mV    -173.5mA   -245.5mA   -105.7mA
-849mV    -71.06mA   -147.7mA   -64.61mA
-787mV    -39.17mA   -92.07mA   -53.7mA
-725mV    -26.41mA   -48.02mA   -41.6mA
-601mV    -11.16mA   -7.552mA   -18.74mA
-384mV    -258.6uA   -114.9uA   -396.2uA
1.5V      -41.68nA   0A         -8.283uA
[POWER_clamp]
|Voltage   I(typ)   I(min)   I(max)
-1.5V     553.8uA    455.7uA    723.9uA
-1.383V   462uA      386.8uA    600.3uA
-1.29V    390.6uA    333.2uA    514.8uA
-1.135V   279.1uA    247uA      410.2uA
-1.011V   206.7uA    182uA      336.5uA
-856mV    145uA      109.7uA    248.3uA
-732mV    104.8uA    66.29uA    183.2uA
-577mV    62.52uA    35.6uA     111.7uA
-422mV    33.03uA    19.13uA    58.98uA
-329mV    22.6uA     13.31uA    51.73uA
12mV      0A         0A         0A
1.5V      0A         0A         0A
[Ramp]
| variable   typ   min   max
dV/dt_r   0.540/0.379n   0.363/0.518n   0.736/0.171n
dV/dt_f   0.583/0.294n   0.369/0.471n   0.754/0.166n
R_load = 50.000
[Rising Waveform]
R_fixture= 50.000
V_fixture= 0.0
V_fixture_min= 0.0
V_fixture_max= 0.0
|time   V(typ)   V(min)   V(max)
0s        304.8uV    218.6uV    443.3uV
805ps     325.5uV    223.4uV    -35.78mV
977ps     399.4uV    223.4uV    767.7mV
1.075ns   164.7uV    223.4uV    1.032V
1.641ns   31.45mV    352.4uV    1.206V
2.074ns   710.8mV    -190.6uV   1.22V
2.95ns    867.9mV    -12.65mV   1.226V
3.624ns   887.8mV    480.4mV    1.227V
4.64ns    896.9mV    576.9mV    1.227V
20ns      899.9mV    604.9mV    1.227V
[Rising Waveform]
R_fixture= 50.000
V_fixture= 1.500
V_fixture_min= 1.430
V_fixture_max= 1.580
|time   V(typ)   V(min)   V(max)
0s        528.5mV    815.7mV    324.1mV
727ps     528.5mV    815.7mV    324.3mV
942ps     528.6mV    815.7mV    1.412V
1.188ns   525.6mV    815.7mV    1.556V
1.408ns   565.7mV    815.5mV    1.568V
1.766ns   1.381V     816mV      1.575V
2.096ns   1.482V     814.1mV    1.578V
3.102ns   1.497V     1.353V     1.58V
3.66ns    1.499V     1.422V     1.58V
20ns      1.5V       1.43V      1.58V
[Falling Waveform]
R_fixture= 50.000
V_fixture= 1.500
V_fixture_min= 1.430
V_fixture_max= 1.580
|time   V(typ)   V(min)   V(max)
0s        1.5V       1.43V      1.58V
830ps     1.5V       1.43V      1.637V
1.108ns   1.5V       1.43V      493.8mV
1.564ns   1.546V     1.43V      341.1mV
2.074ns   718.3mV    1.43V      329.1mV
2.648ns   554.5mV    1.431V     325.1mV
3.118ns   539.2mV    1.463V     324.4mV
3.691ns   532.7mV    972.1mV    324.1mV
4.638ns   529.5mV    833.1mV    324.2mV
20ns      528.4mV    815.7mV    324.1mV
[Falling Waveform]
R_fixture= 50.000
V_fixture= 0.0
V_fixture_min= 0.0
V_fixture_max= 0.0
|time   V(typ)   V(min)   V(max)
0s        899.9mV    604.9mV    1.227V
772ps     900mV      605mV      1.22V
969ps     899.9mV    605mV      153.3mV
1.272ns   898.9mV    605mV      15.71mV
1.504ns   856.4mV    605mV      7.917mV
1.835ns   100.8mV    604.9mV    3.552mV
2.319ns   9.077mV    603.7mV    1.233mV
3.331ns   1.93mV     66.07mV    516.7uV
3.904ns   846.3uV    6.713mV    477uV
20ns      304.3uV    218.6uV    442.8uV
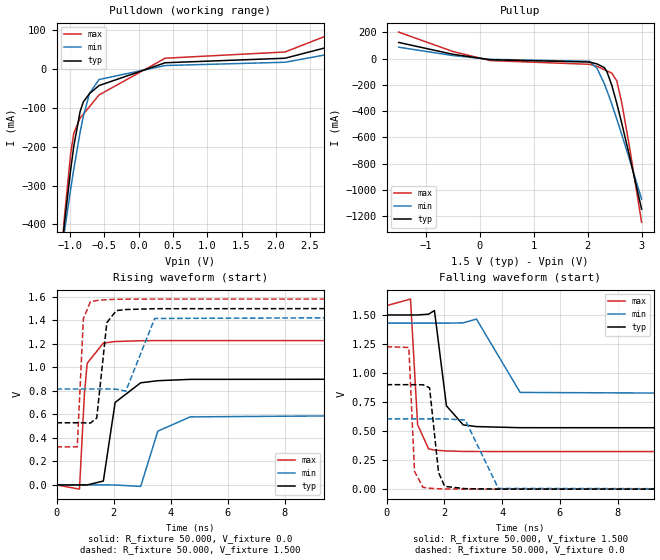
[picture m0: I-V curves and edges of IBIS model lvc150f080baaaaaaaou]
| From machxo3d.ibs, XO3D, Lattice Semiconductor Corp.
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|   Model lvc150f080baaaaaaaou
[Model] lvc150f080baaaaaaaou
Model_type Output
Polarity   Non-Inverting
Enable   Active-High
Vmeas =  0.750V
Cref =  0.0F
Rref =  1.000M
Vref =  0.0V
C_comp   4.200pF   3.800pF   7.500pF
[Temperature Range]   25.000   0.105k   -40.000
[Voltage Range]   1.500V   1.430V   1.580V
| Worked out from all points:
|   slope of the pulldown table from 0 to 0.225 V, typ, clamps not added: 20.4 ohm
|   slope of the pullup table from 0 to 0.225 V, typ, clamps not added: 23.3 ohm
|   rising waveform, R_fixture 50.000, V_fixture 0.0: 20-80 % time 384ps typ, 516ps min, 169ps max; typ from 0 V to 0.9 V
|   rising waveform, R_fixture 50.000, V_fixture 1.500: 20-80 % time 238ps typ, 414ps min, 114ps max; typ from 0.529 V to 1.5 V
|   falling waveform, R_fixture 50.000, V_fixture 1.500: 20-80 % time 302ps typ, 467ps min, 166ps max; typ from 1.5 V to 0.528 V
|   falling waveform, R_fixture 50.000, V_fixture 0.0: 20-80 % time 212ps typ, 373ps min, 105ps max; typ from 0.9 V to 0 V
[Pulldown]
|Voltage   I(typ)   I(min)   I(max)
-1.5V     -1.126A    -962mA     -1.414A
-1.132V   -475.7mA   -477.5mA   -486mA
-1.086V   -400.2mA   -420.1mA   -383.6mA
-994mV    -259.5mA   -309.7mA   -217.9mA
-948mV    -198.4mA   -257.5mA   -165.4mA
-856mV    -109.3mA   -162.8mA   -125.9mA
-810mV    -84.87mA   -122.4mA   -116.7mA
-718mV    -62.88mA   -62.28mA   -96.49mA
-580mV    -42.43mA   -26.88mA   -66.6mA
386mV     16.35mA    9.186mA    28.07mA
2.134V    27.98mA    17.63mA    44.05mA
3V        67.45mA    45.52mA    103.7mA
[Pullup]
|Voltage   I(typ)   I(min)   I(max)
-1.5V     122.9mA    86.62mA    201.7mA
-496mV    32.59mA    22.99mA    53.75mA
194mV     -8.541mA   -5.66mA    -15.21mA
2.034V    -26.41mA   -21.06mA   -43.66mA
2.172V    -40.47mA   -72.01mA   -59.1mA
2.31V     -69.15mA   -192.2mA   -84.82mA
2.356V    -98.37mA   -241.2mA   -94mA
2.448V    -203.4mA   -347.3mA   -111mA
2.54V     -340.9mA   -460.5mA   -169.2mA
2.632V    -492.2mA   -577.9mA   -335.8mA
2.77V     -731.7mA   -759.3mA   -659.4mA
3V        -1.146A    -1.07A     -1.246A
[Ramp]
| variable   typ   min   max
dV/dt_r   0.540/0.376n   0.363/0.519n   0.736/0.170n
dV/dt_f   0.583/0.294n   0.369/0.470n   0.754/0.166n
R_load = 50.000
[Rising Waveform]
R_fixture= 50.000
V_fixture= 0.0
V_fixture_min= 0.0
V_fixture_max= 0.0
|time   V(typ)   V(min)   V(max)
0s        304.8uV    218.6uV    443.3uV
805ps     349.3uV    246.7uV    -35.85mV
978ps     380.5uV    221.7uV    772.7mV
1.075ns   110.5uV    221.7uV    1.034V
1.642ns   33.09mV    356.1uV    1.206V
2.056ns   701.4mV    -191uV     1.219V
2.95ns    868.2mV    -12.72mV   1.226V
3.553ns   886.1mV    457.5mV    1.227V
4.686ns   897.4mV    578.5mV    1.227V
20ns      899.9mV    604.9mV    1.227V
[Rising Waveform]
R_fixture= 50.000
V_fixture= 1.500
V_fixture_min= 1.430
V_fixture_max= 1.580
|time   V(typ)   V(min)   V(max)
0s        528.5mV    815.7mV    324.1mV
727ps     528.5mV    815.7mV    324.2mV
942ps     528.5mV    815.7mV    1.413V
1.188ns   525.6mV    815.7mV    1.557V
1.41ns    568.8mV    815.6mV    1.568V
1.764ns   1.379V     816.4mV    1.575V
2.097ns   1.482V     814.1mV    1.578V
2.428ns   1.491V     797mV      1.579V
3.443ns   1.498V     1.415V     1.58V
20ns      1.5V       1.43V      1.58V
[Falling Waveform]
R_fixture= 50.000
V_fixture= 1.500
V_fixture_min= 1.430
V_fixture_max= 1.580
|time   V(typ)   V(min)   V(max)
0s        1.5V       1.43V      1.58V
830ps     1.5V       1.43V      1.637V
1.075ns   1.5V       1.43V      555.9mV
1.455ns   1.507V     1.43V      347.3mV
1.658ns   1.538V     1.43V      337.1mV
2.074ns   717.8mV    1.43V      329mV
2.654ns   553.7mV    1.432V     325mV
3.112ns   539mV      1.465V     324.5mV
4.624ns   529.5mV    833.1mV    324.1mV
20ns      528.4mV    815.7mV    324.1mV
[Falling Waveform]
R_fixture= 50.000
V_fixture= 0.0
V_fixture_min= 0.0
V_fixture_max= 0.0
|time   V(typ)   V(min)   V(max)
0s        899.9mV    604.9mV    1.227V
772ps     900mV      605mV      1.22V
969ps     899.9mV    605mV      152.9mV
1.264ns   899mV      605mV      15.57mV
1.49ns    873mV      605mV      8.258mV
1.801ns   143.2mV    605mV      3.826mV
2.013ns   24.34mV    605.5mV    2.388mV
2.725ns   4.46mV     595.5mV    731.9uV
3.87ns    980.8uV    6.782mV    502.1uV
20ns      304.6uV    218.4uV    443.2uV
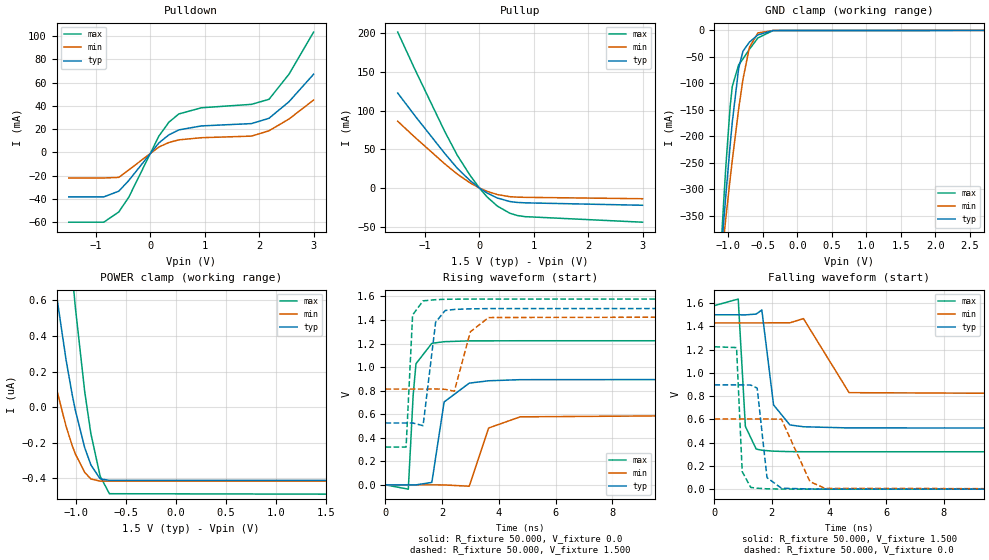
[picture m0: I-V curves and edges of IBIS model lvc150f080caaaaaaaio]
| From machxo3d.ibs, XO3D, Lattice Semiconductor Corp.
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|   Model lvc150f080caaaaaaaio
[Model] lvc150f080caaaaaaaio
Model_type I/O
Polarity   Non-Inverting
Enable   Active-Low
Vinl =  0.375V
Vinh =  1.125V
Vmeas =  0.750V
Cref =  0.0F
Rref =  1.000M
Vref =  0.0V
C_comp   4.200pF   3.800pF   7.500pF
[Temperature Range]   25.000   0.105k   -40.000
[Voltage Range]   1.500V   1.430V   1.580V
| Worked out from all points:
|   slope of the pulldown table from 0 to 0.225 V, typ, clamps not added: 20.4 ohm
|   slope of the pullup table from 0 to 0.225 V, typ, clamps not added: 23.3 ohm
|   GND clamp passes 1 mA (typ) near -0.43 V on its own axis
|   rising waveform, R_fixture 50.000, V_fixture 0.0: 20-80 % time 385ps typ, 511ps min, 171ps max; typ from 0 V to 0.896 V
|   rising waveform, R_fixture 50.000, V_fixture 1.500: 20-80 % time 240ps typ, 415ps min, 114ps max; typ from 0.526 V to 1.5 V
|   falling waveform, R_fixture 50.000, V_fixture 1.500: 20-80 % time 300ps typ, 472ps min, 164ps max; typ from 1.5 V to 0.526 V
|   falling waveform, R_fixture 50.000, V_fixture 0.0: 20-80 % time 211ps typ, 372ps min, 105ps max; typ from 0.896 V to 0 V
[Pulldown]
|Voltage   I(typ)   I(min)   I(max)
-1.5V     -38.2mA    -21.99mA   -59.93mA
-856mV    -38.2mA    -21.99mA   -59.93mA
-580mV    -33.29mA   -21.45mA   -51.12mA
-396mV    -24.09mA   -14.99mA   -38.38mA
156mV     8.127mA    4.623mA    13.97mA
340mV     15.07mA    8.487mA    25.9mA
524mV     19.32mA    10.78mA    33.03mA
938mV     22.73mA    12.61mA    38.32mA
1.858V    24.73mA    13.98mA    41.25mA
2.18V     29.26mA    18.55mA    45.57mA
2.548V    43.53mA    28.67mA    67.14mA
3V        67.11mA    44.96mA    103.3mA
[Pullup]
|Voltage   I(typ)   I(min)   I(max)
-1.5V     122.6mA    86.12mA    201.3mA
-1.186V   93.41mA    65.57mA    153.4mA
-634mV    44.42mA    31.03mA    72.67mA
-404mV    25.36mA    17.82mA    42.1mA
-174mV    9.761mA    6.692mA    16.69mA
10mV      -505.5uA   -338.4uA   -886.9uA
148mV     -6.75mA    -4.487mA   -11.97mA
332mV     -12.99mA   -8.529mA   -23.46mA
562mV     -17.55mA   -11.28mA   -32.68mA
700mV     -18.72mA   -11.87mA   -35.61mA
838mV     -19.2mA    -12.1mA    -37.04mA
3V        -22.36mA   -13.9mA    -44.21mA
[GND_clamp]
|Voltage   I(typ)   I(min)   I(max)
-1.5V     -1.124A    -960.6mA   -1.411A
-1.097V   -411.6mA   -430.5mA   -393mA
-1.066V   -360.7mA   -392.1mA   -323mA
-1.035V   -311mA     -354.2mA   -256.8mA
-973mV    -216.9mA   -280.8mA   -144.3mA
-942mV    -173.5mA   -245.5mA   -105.7mA
-849mV    -71.09mA   -147.7mA   -64.66mA
-787mV    -39.21mA   -92.09mA   -53.75mA
-694mV    -22.05mA   -31.84mA   -35.55mA
-570mV    -8.285mA   -4.678mA   -14.06mA
-353mV    -178.3uA   -91.12uA   -279.1uA
3V        108.1uA    41.24uA    254.4uA
[POWER_clamp]
|Voltage   I(typ)   I(min)   I(max)
-1.5V     2.264uA    1.09uA     5.325uA
-1.383V   1.543uA    646.9nA    3.832uA
-1.29V    1.045uA    348.8nA    2.802uA
-1.197V   619.1nA    96nA       1.914uA
-1.104V   264.3nA    -108.5nA   1.168uA
-1.042V   67.89nA    -217.5nA   747.1nA
-1.011V   -18.17nA   -263.5nA   559.8nA
-918mV    -227nA     -366.2nA   89.66nA
-856mV    -323.9nA   -403.7nA   -147.4nA
-763mV    -403.1nA   -415.9nA   -387.4nA
-670mV    -411.5nA   -415.9nA   -486.6nA
1.5V      -411.5nA   -415.9nA   -489.1nA
[Ramp]
| variable   typ   min   max
dV/dt_r   0.538/0.379n   0.362/0.518n   0.734/0.171n
dV/dt_f   0.584/0.292n   0.369/0.469n   0.754/0.165n
R_load = 50.000
[Rising Waveform]
R_fixture= 50.000
V_fixture= 0.0
V_fixture_min= 0.0
V_fixture_max= 0.0
|time   V(typ)   V(min)   V(max)
0s        2.856nV    35.01nV    1.357nV
805ps     20.22uV    28.73uV    -36.47mV
977ps     76.37uV    3.733uV    764.9mV
1.076ns   -187.6uV   3.733uV    1.029V
1.635ns   20.82mV    136.5uV    1.202V
2.068ns   704.2mV    -407.4uV   1.216V
2.954ns   864mV      -11.43mV   1.223V
3.637ns   884mV      482.7mV    1.223V
4.749ns   893.4mV    577.8mV    1.224V
20ns      896mV      602.8mV    1.224V
[Rising Waveform]
R_fixture= 50.000
V_fixture= 1.500
V_fixture_min= 1.430
V_fixture_max= 1.580
|time   V(typ)   V(min)   V(max)
0s        525.6mV    813.6mV    321.6mV
727ps     525.6mV    813.6mV    321.6mV
957ps     525.7mV    813.6mV    1.443V
1.326ns   502.8mV    813.5mV    1.563V
1.769ns   1.382V     814.5mV    1.573V
2.106ns   1.481V     811.4mV    1.576V
2.428ns   1.49V      795mV      1.577V
2.993ns   1.495V     1.3V       1.578V
3.637ns   1.497V     1.421V     1.578V
20ns      1.499V     1.429V     1.578V
[Falling Waveform]
R_fixture= 50.000
V_fixture= 1.500
V_fixture_min= 1.430
V_fixture_max= 1.580
|time   V(typ)   V(min)   V(max)
0s        1.499V     1.429V     1.578V
829ps     1.499V     1.429V     1.634V
1.079ns   1.498V     1.429V     539.8mV
1.455ns   1.505V     1.429V     344.9mV
1.653ns   1.54V      1.429V     334.7mV
2.062ns   724.3mV    1.43V      326.6mV
2.632ns   552.1mV    1.43V      322.5mV
3.105ns   536.4mV    1.466V     321.9mV
4.697ns   526.3mV    829.5mV    321.6mV
20ns      525.5mV    813.6mV    321.6mV
[Falling Waveform]
R_fixture= 50.000
V_fixture= 0.0
V_fixture_min= 0.0
V_fixture_max= 0.0
|time   V(typ)   V(min)   V(max)
0s        896mV      602.8mV    1.224V
771ps     896mV      602.8mV    1.217V
968ps     896mV      602.8mV    151.1mV
1.266ns   895.1mV    602.8mV    15.06mV
1.49ns    868.8mV    602.8mV    7.918mV
1.834ns   99.33mV    602.8mV    3.025mV
2.337ns   8.214mV    601.3mV    756.7uV
3.331ns   1.595mV    64.97mV    121.7uV
3.853ns   688.9uV    7.165mV    28.52uV
20ns      -95.6nV    -522.9nV   -434.6nV
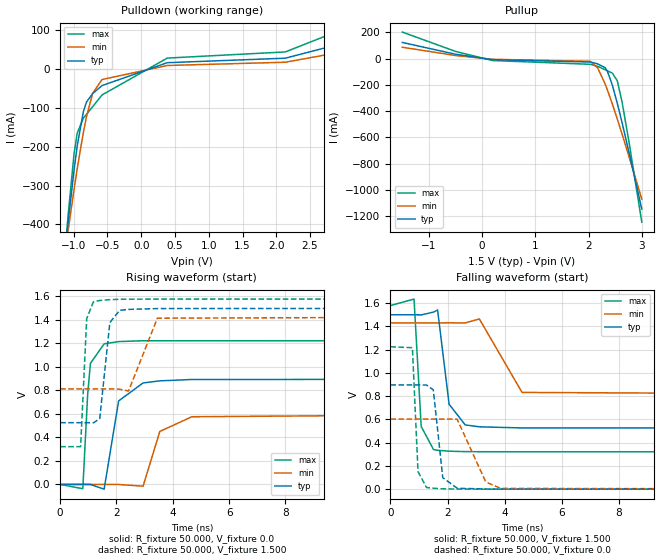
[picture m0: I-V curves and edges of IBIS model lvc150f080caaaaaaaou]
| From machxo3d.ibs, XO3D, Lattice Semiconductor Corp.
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|   Model lvc150f080caaaaaaaou
[Model] lvc150f080caaaaaaaou
Model_type Output
Polarity   Non-Inverting
Enable   Active-High
Vmeas =  0.750V
Cref =  0.0F
Rref =  1.000M
Vref =  0.0V
C_comp   4.200pF   3.800pF   7.500pF
[Temperature Range]   25.000   0.105k   -40.000
[Voltage Range]   1.500V   1.430V   1.580V
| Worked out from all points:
|   slope of the pulldown table from 0 to 0.225 V, typ, clamps not added: 20.3 ohm
|   slope of the pullup table from 0 to 0.225 V, typ, clamps not added: 23.3 ohm
|   rising waveform, R_fixture 50.000, V_fixture 0.0: 20-80 % time 382ps typ, 509ps min, 170ps max; typ from 0 V to 0.896 V
|   rising waveform, R_fixture 50.000, V_fixture 1.500: 20-80 % time 240ps typ, 425ps min, 114ps max; typ from 0.526 V to 1.5 V
|   falling waveform, R_fixture 50.000, V_fixture 1.500: 20-80 % time 301ps typ, 470ps min, 164ps max; typ from 1.5 V to 0.526 V
|   falling waveform, R_fixture 50.000, V_fixture 0.0: 20-80 % time 211ps typ, 371ps min, 104ps max; typ from 0.896 V to 0 V
[Pulldown]
|Voltage   I(typ)   I(min)   I(max)
-1.5V     -1.126A    -962mA     -1.414A
-1.132V   -475.8mA   -477.5mA   -486mA
-1.086V   -400.2mA   -420.1mA   -383.6mA
-994mV    -259.6mA   -309.7mA   -218mA
-948mV    -198.5mA   -257.5mA   -165.4mA
-856mV    -109.3mA   -162.8mA   -125.9mA
-810mV    -84.9mA    -122.5mA   -116.7mA
-718mV    -62.92mA   -62.31mA   -96.54mA
-580mV    -42.48mA   -26.92mA   -66.67mA
386mV     16.44mA    9.226mA    28.28mA
2.134V    28.02mA    17.62mA    44.16mA
3V        67.22mA    45.01mA    103.6mA
[Pullup]
|Voltage   I(typ)   I(min)   I(max)
-1.5V     122.7mA    86.16mA    201.6mA
-496mV    32.64mA    23mA       53.88mA
194mV     -8.431mA   -5.618mA   -14.96mA
2.034V    -26.45mA   -21.08mA   -43.74mA
2.172V    -40.49mA   -72.02mA   -59.15mA
2.31V     -69.17mA   -192.2mA   -84.85mA
2.356V    -98.39mA   -241.2mA   -94.02mA
2.448V    -203.4mA   -347.4mA   -111.1mA
2.54V     -340.9mA   -460.5mA   -169.2mA
2.632V    -492.3mA   -577.9mA   -335.8mA
2.77V     -731.7mA   -759.3mA   -659.4mA
3V        -1.146A    -1.07A     -1.246A
[Ramp]
| variable   typ   min   max
dV/dt_r   0.538/0.376n   0.362/0.517n   0.734/0.170n
dV/dt_f   0.584/0.291n   0.369/0.469n   0.754/0.164n
R_load = 50.000
[Rising Waveform]
R_fixture= 50.000
V_fixture= 0.0
V_fixture_min= 0.0
V_fixture_max= 0.0
|time   V(typ)   V(min)   V(max)
0s        2.83nV     35.12nV    1.331nV
805ps     20.13uV    27.55uV    -36.52mV
977ps     100.6uV    2.574uV    765.9mV
1.075ns   -139.8uV   2.574uV    1.03V
1.562ns   -40.3mV    88.54uV    1.197V
2.077ns   710.8mV    -409.3uV   1.216V
2.945ns   863.8mV    -14.99mV   1.223V
3.54ns    881.8mV    451.1mV    1.223V
4.678ns   893.2mV    576.2mV    1.223V
20ns      896mV      602.8mV    1.224V
[Rising Waveform]
R_fixture= 50.000
V_fixture= 1.500
V_fixture_min= 1.430
V_fixture_max= 1.580
|time   V(typ)   V(min)   V(max)
0s        525.6mV    813.6mV    321.6mV
727ps     525.6mV    813.7mV    321.6mV
943ps     525.6mV    813.7mV    1.411V
1.178ns   523.8mV    813.6mV    1.554V
1.406ns   559.6mV    813.4mV    1.566V
1.765ns   1.378V     813.9mV    1.573V
2.115ns   1.482V     810.6mV    1.576V
2.428ns   1.49V      795mV      1.577V
3.453ns   1.497V     1.415V     1.578V
20ns      1.499V     1.429V     1.578V
[Falling Waveform]
R_fixture= 50.000
V_fixture= 1.500
V_fixture_min= 1.430
V_fixture_max= 1.580
|time   V(typ)   V(min)   V(max)
0s        1.499V     1.429V     1.578V
829ps     1.499V     1.429V     1.634V
1.079ns   1.498V     1.429V     539.1mV
1.51ns    1.522V     1.429V     340.6mV
1.653ns   1.54V      1.429V     334.2mV
2.056ns   729.6mV    1.43V      326.4mV
2.619ns   552.4mV    1.429V     322.7mV
3.114ns   535.9mV    1.463V     321.9mV
4.607ns   526.3mV    831.5mV    321.6mV
20ns      525.5mV    813.6mV    321.6mV
[Falling Waveform]
R_fixture= 50.000
V_fixture= 0.0
V_fixture_min= 0.0
V_fixture_max= 0.0
|time   V(typ)   V(min)   V(max)
0s        896mV      602.8mV    1.224V
772ps     896mV      602.8mV    1.216V
968ps     896mV      602.8mV    150.7mV
1.265ns   895.1mV    602.8mV    14.69mV
1.503ns   853.5mV    602.8mV    7.704mV
1.834ns   98.9mV     602.8mV    3.091mV
2.337ns   7.965mV    601.4mV    781.7uV
3.338ns   1.462mV    61.86mV    67.74uV
3.862ns   599.8uV    6.599mV    31.65uV
20ns      -186.7nV   -430.2nV   12.42nV
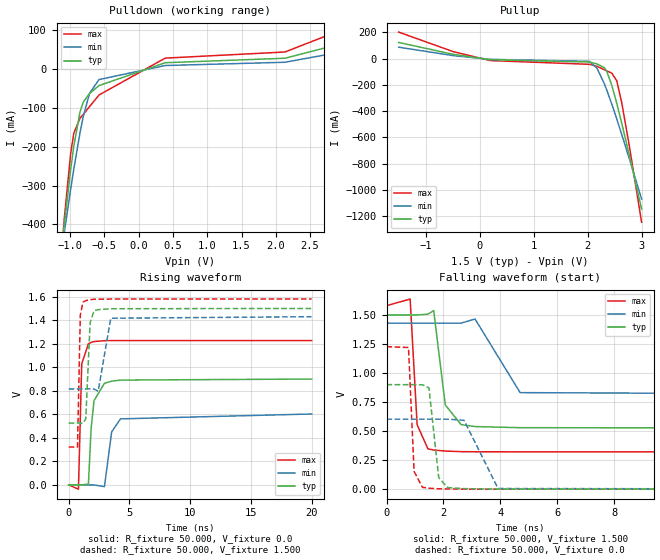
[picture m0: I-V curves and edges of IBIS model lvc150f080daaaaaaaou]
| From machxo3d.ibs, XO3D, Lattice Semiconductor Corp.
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|   Model lvc150f080daaaaaaaou
[Model] lvc150f080daaaaaaaou
Model_type Output
Polarity   Non-Inverting
Enable   Active-High
Vmeas =  0.750V
Cref =  0.0F
Rref =  1.000M
Vref =  0.0V
C_comp   4.200pF   3.800pF   7.500pF
[Temperature Range]   25.000   0.105k   -40.000
[Voltage Range]   1.500V   1.430V   1.580V
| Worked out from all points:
|   slope of the pulldown table from 0 to 0.225 V, typ, clamps not added: 20.3 ohm
|   slope of the pullup table from 0 to 0.225 V, typ, clamps not added: 23.3 ohm
|   rising waveform, R_fixture 50.000, V_fixture 0.0: 20-80 % time 387ps typ, 509ps min, 172ps max; typ from 0 V to 0.9 V
|   rising waveform, R_fixture 50.000, V_fixture 1.500: 20-80 % time 240ps typ, 424ps min, 114ps max; typ from 0.526 V to 1.5 V
|   falling waveform, R_fixture 50.000, V_fixture 1.500: 20-80 % time 305ps typ, 467ps min, 167ps max; typ from 1.5 V to 0.526 V
|   falling waveform, R_fixture 50.000, V_fixture 0.0: 20-80 % time 212ps typ, 372ps min, 105ps max; typ from 0.9 V to 0 V
[Pulldown]
|Voltage   I(typ)   I(min)   I(max)
-1.5V     -1.126A    -962mA     -1.414A
-1.132V   -475.8mA   -477.5mA   -486mA
-1.086V   -400.2mA   -420.1mA   -383.6mA
-994mV    -259.6mA   -309.7mA   -218mA
-948mV    -198.5mA   -257.5mA   -165.4mA
-856mV    -109.3mA   -162.8mA   -125.9mA
-810mV    -84.9mA    -122.5mA   -116.7mA
-718mV    -62.92mA   -62.31mA   -96.54mA
-580mV    -42.48mA   -26.92mA   -66.67mA
386mV     16.44mA    9.226mA    28.28mA
2.134V    27.98mA    17.63mA    44.05mA
3V        67.45mA    45.52mA    103.7mA
[Pullup]
|Voltage   I(typ)   I(min)   I(max)
-1.5V     122.9mA    86.62mA    201.7mA
-496mV    32.59mA    22.99mA    53.75mA
194mV     -8.541mA   -5.66mA    -15.21mA
2.034V    -26.45mA   -21.08mA   -43.74mA
2.172V    -40.49mA   -72.02mA   -59.15mA
2.31V     -69.17mA   -192.2mA   -84.85mA
2.356V    -98.39mA   -241.2mA   -94.02mA
2.448V    -203.4mA   -347.4mA   -111.1mA
2.54V     -340.9mA   -460.5mA   -169.2mA
2.632V    -492.3mA   -577.9mA   -335.8mA
2.77V     -731.7mA   -759.3mA   -659.4mA
3V        -1.146A    -1.07A     -1.246A
[Ramp]
| variable   typ   min   max
dV/dt_r   0.540/0.382n   0.362/0.517n   0.736/0.172n
dV/dt_f   0.585/0.296n   0.369/0.470n   0.755/0.167n
R_load = 50.000
[Rising Waveform]
R_fixture= 50.000
V_fixture= 0.0
V_fixture_min= 0.0
V_fixture_max= 0.0
|time   V(typ)   V(min)   V(max)
0s        2.83nV     35.12nV    1.331nV
805ps     20.13uV    27.53uV    -36.52mV
1.075ns   -139.8uV   2.571uV    1.03V
1.626ns   7.08mV     141.2uV    1.201V
1.849ns   480.4mV    -86.79uV   1.211V
2.087ns   716.4mV    -409.3uV   1.219V
2.945ns   863.8mV    -14.99mV   1.226V
3.54ns    881.8mV    451.1mV    1.227V
4.267ns   891mV      561.2mV    1.227V
20ns      899.9mV    602.8mV    1.227V
[Rising Waveform]
R_fixture= 50.000
V_fixture= 1.500
V_fixture_min= 1.430
V_fixture_max= 1.580
|time   V(typ)   V(min)   V(max)
0s        525.6mV    815.7mV    321.6mV
727ps     525.6mV    815.7mV    321.6mV
957ps     525.9mV    815.7mV    1.444V
1.178ns   523.8mV    815.7mV    1.554V
1.406ns   559.6mV    815.6mV    1.566V
1.765ns   1.378V     816.4mV    1.575V
2.089ns   1.481V     814.6mV    1.578V
2.428ns   1.49V      797mV      1.579V
3.468ns   1.498V     1.417V     1.58V
20ns      1.5V       1.43V      1.58V
[Falling Waveform]
R_fixture= 50.000
V_fixture= 1.500
V_fixture_min= 1.430
V_fixture_max= 1.580
|time   V(typ)   V(min)   V(max)
0s        1.5V       1.43V      1.58V
830ps     1.5V       1.43V      1.637V
1.075ns   1.5V       1.43V      555.9mV
1.455ns   1.507V     1.43V      347.3mV
1.658ns   1.538V     1.43V      337.1mV
2.065ns   726mV      1.43V      328.3mV
2.622ns   555.7mV    1.43V      323mV
3.112ns   539mV      1.465V     322mV
4.697ns   529.4mV    831.3mV    321.6mV
20ns      525.5mV    815.7mV    321.6mV
[Falling Waveform]
R_fixture= 50.000
V_fixture= 0.0
V_fixture_min= 0.0
V_fixture_max= 0.0
|time   V(typ)   V(min)   V(max)
0s        899.9mV    602.8mV    1.227V
772ps     900mV      602.8mV    1.22V
969ps     899.9mV    602.8mV    152.9mV
1.264ns   899mV      602.8mV    15.57mV
1.49ns    873mV      602.8mV    8.258mV
1.835ns   100.4mV    602.8mV    3.262mV
2.142ns   13.95mV    603.2mV    1.903mV
2.725ns   4.503mV    593.3mV    400.2uV
3.92ns    720.4uV    5.803mV    54.74uV
20ns      -108.3nV   -430.2nV   -481.6nV
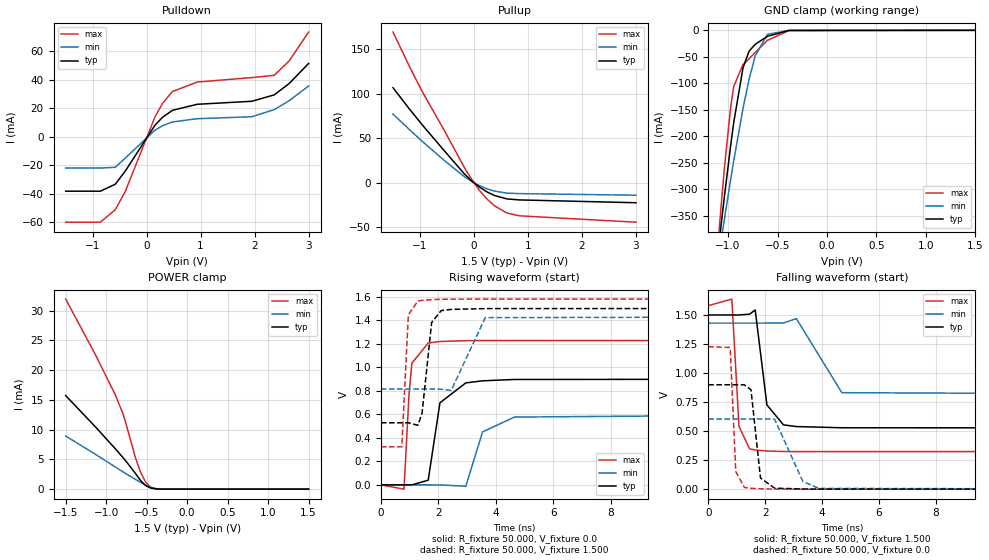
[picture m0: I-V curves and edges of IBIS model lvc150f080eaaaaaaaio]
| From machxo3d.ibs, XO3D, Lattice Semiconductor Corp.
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|   Model lvc150f080eaaaaaaaio
[Model] lvc150f080eaaaaaaaio
Model_type I/O
Polarity   Non-Inverting
Enable   Active-Low
Vinl =  0.375V
Vinh =  1.125V
Vmeas =  0.750V
Cref =  0.0F
Rref =  1.000M
Vref =  0.0V
C_comp   4.200pF   3.800pF   7.500pF
[Temperature Range]   25.000   0.105k   -40.000
[Voltage Range]   1.500V   1.430V   1.580V
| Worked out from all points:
|   slope of the pulldown table from 0 to 0.225 V, typ, clamps not added: 20.4 ohm
|   slope of the pullup table from 0 to 0.225 V, typ, clamps not added: 23.3 ohm
|   GND clamp passes 1 mA (typ) near -0.44 V on its own axis
|   POWER clamp passes 1 mA (typ) near -0.55 V on its own axis
|   rising waveform, R_fixture 50.000, V_fixture 0.0: 20-80 % time 388ps typ, 514ps min, 171ps max; typ from 0 V to 0.899 V
|   rising waveform, R_fixture 50.000, V_fixture 1.500: 20-80 % time 239ps typ, 413ps min, 114ps max; typ from 0.528 V to 1.5 V
|   falling waveform, R_fixture 50.000, V_fixture 1.500: 20-80 % time 302ps typ, 470ps min, 166ps max; typ from 1.5 V to 0.528 V
|   falling waveform, R_fixture 50.000, V_fixture 0.0: 20-80 % time 212ps typ, 373ps min, 105ps max; typ from 0.899 V to 0 V
[Pulldown]
|Voltage   I(typ)   I(min)   I(max)
-1.5V     -38.2mA    -21.99mA   -59.93mA
-856mV    -38.2mA    -21.99mA   -59.93mA
-580mV    -33.29mA   -21.45mA   -51.12mA
-396mV    -24.09mA   -14.99mA   -38.38mA
156mV     8.127mA    4.623mA    13.97mA
294mV     13.59mA    7.677mA    23.37mA
478mV     18.49mA    10.34mA    31.68mA
938mV     22.73mA    12.61mA    38.32mA
1.95V     24.84mA    13.99mA    41.43mA
2.364V    29.33mA    18.99mA    43.04mA
2.64V     37.26mA    25.2mA     53.1mA
3V        51.33mA    35.46mA    73.33mA
[Pullup]
|Voltage   I(typ)   I(min)   I(max)
-1.5V     106.8mA    77.16mA    169.3mA
-1.186V   82.13mA    59.23mA    129.4mA
-956mV    64.9mA     46.45mA    102.2mA
-542mV    35.44mA    24.73mA    57.94mA
-174mV    9.761mA    6.692mA    16.69mA
-36mV     1.872mA    1.261mA    3.264mA
102mV     -4.819mA   -3.211mA   -8.515mA
240mV     -10.16mA   -6.718mA   -18.18mA
378mV     -14.18mA   -9.28mA    -25.75mA
608mV     -18.05mA   -11.55mA   -33.86mA
838mV     -19.2mA    -12.1mA    -37.04mA
3V        -22.36mA   -13.9mA    -44.21mA
[GND_clamp]
|Voltage   I(typ)   I(min)   I(max)
-1.5V     -1.124A    -960.6mA   -1.411A
-1.097V   -411.6mA   -430.5mA   -392.9mA
-1.066V   -360.7mA   -392.1mA   -323mA
-1.035V   -311mA     -354.2mA   -256.7mA
-973mV    -216.8mA   -280.8mA   -144.2mA
-942mV    -173.4mA   -245.5mA   -105.6mA
-849mV    -71.05mA   -147.7mA   -64.59mA
-787mV    -39.16mA   -92.07mA   -53.68mA
-725mV    -26.4mA    -48.02mA   -41.58mA
-601mV    -11.15mA   -7.544mA   -18.72mA
-384mV    -236.4uA   -103.3uA   -351.1uA
1.5V      0A         0A         0A
[POWER_clamp]
|Voltage   I(typ)   I(min)   I(max)
-1.5V     15.72mA    8.929mA    31.93mA
-1.135V   10.5mA     5.879mA    22.65mA
-887mV    6.787mA    3.722mA    15.85mA
-794mV    5.333mA    2.928mA    12.72mA
-763mV    4.831mA    2.666mA    11.38mA
-639mV    2.654mA    1.642mA    5.303mA
-577mV    1.493mA    1.154mA    2.909mA
-515mV    627.3uA    700.9uA    1.235mA
-453mV    200.7uA    325.5uA    363.9uA
-391mV    56.19uA    99.29uA    82.51uA
-298mV    7.73uA     11.12uA    7.668uA
1.5V      0A         0A         4.131nA
[Ramp]
| variable   typ   min   max
dV/dt_r   0.540/0.379n   0.363/0.518n   0.736/0.171n
dV/dt_f   0.583/0.303n   0.369/0.470n   0.754/0.166n
R_load = 50.000
[Rising Waveform]
R_fixture= 50.000
V_fixture= 0.0
V_fixture_min= 0.0
V_fixture_max= 0.0
|time   V(typ)   V(min)   V(max)
0s        2.959nV    35.35nV    1.474nV
805ps     20.67uV    3.785uV    -36.58mV
978ps     75.17uV    3.785uV    770.1mV
1.077ns   -196.1uV   3.785uV    1.034V
1.646ns   39.58mV    137.4uV    1.206V
2.054ns   697.7mV    -407.4uV   1.219V
2.954ns   867.2mV    -11.52mV   1.226V
3.537ns   884.8mV    450mV      1.227V
4.647ns   896.2mV    576.5mV    1.227V
20ns      899.2mV    604.4mV    1.227V
[Rising Waveform]
R_fixture= 50.000
V_fixture= 1.500
V_fixture_min= 1.430
V_fixture_max= 1.580
|time   V(typ)   V(min)   V(max)
0s        527.9mV    815.2mV    323.4mV
727ps     527.8mV    815.3mV    323.5mV
957ps     528.1mV    815.2mV    1.447V
1.285ns   506.5mV    815.1mV    1.563V
1.432ns   608.1mV    814.9mV    1.569V
1.766ns   1.381V     815.9mV    1.575V
2.098ns   1.482V     813.5mV    1.578V
2.443ns   1.492V     803mV      1.579V
3.631ns   1.499V     1.422V     1.58V
20ns      1.5V       1.43V      1.58V
[Falling Waveform]
R_fixture= 50.000
V_fixture= 1.500
V_fixture_min= 1.430
V_fixture_max= 1.580
|time   V(typ)   V(min)   V(max)
0s        1.5V       1.43V      1.58V
830ps     1.5V       1.43V      1.637V
1.082ns   1.5V       1.43V      539.7mV
1.454ns   1.507V     1.43V      347.5mV
1.653ns   1.543V     1.43V      337.5mV
2.065ns   725.1mV    1.43V      328.4mV
2.648ns   553.7mV    1.431V     324.3mV
3.1ns     539.1mV    1.469V     323.7mV
4.701ns   528.7mV    830.9mV    323.5mV
20ns      527.7mV    815.2mV    323.4mV
[Falling Waveform]
R_fixture= 50.000
V_fixture= 0.0
V_fixture_min= 0.0
V_fixture_max= 0.0
|time   V(typ)   V(min)   V(max)
0s        899.2mV    604.4mV    1.227V
772ps     899.2mV    604.4mV    1.22V
969ps     899.2mV    604.4mV    152.2mV
1.272ns   898.3mV    604.4mV    15.23mV
1.504ns   855.6mV    604.4mV    7.46mV
1.839ns   96.16mV    604.4mV    3.113mV
2.335ns   8.434mV    602.9mV    799.6uV
3.331ns   1.641mV    65.67mV    75.36uV
3.904ns   556.1uV    6.479mV    34.85uV
20ns      -297.8nV   -32.23nV   -526.2nV
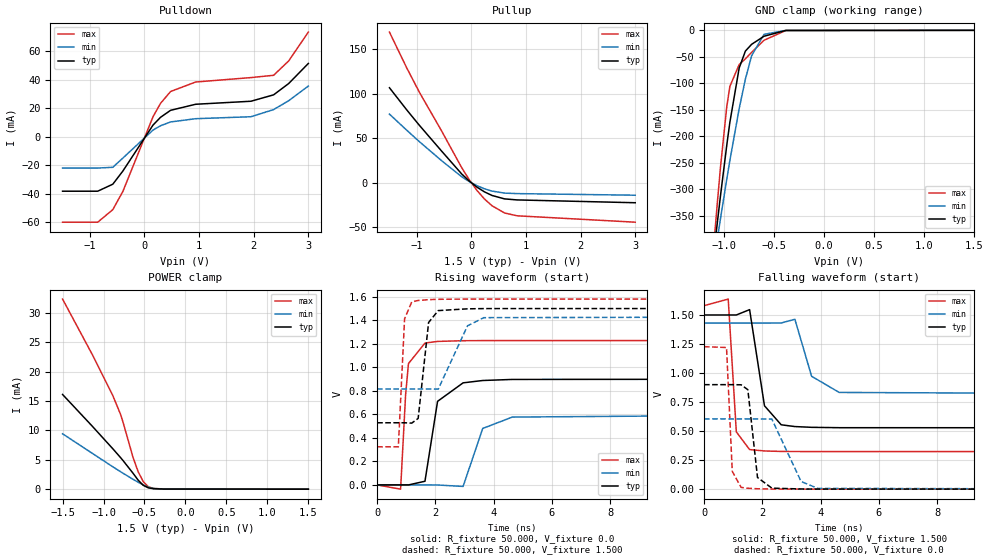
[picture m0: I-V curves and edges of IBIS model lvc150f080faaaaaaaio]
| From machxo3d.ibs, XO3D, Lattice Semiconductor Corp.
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|   Model lvc150f080faaaaaaaio
[Model] lvc150f080faaaaaaaio
Model_type I/O
Polarity   Non-Inverting
Enable   Active-Low
Vinl =  0.375V
Vinh =  1.125V
Vmeas =  0.750V
Cref =  0.0F
Rref =  1.000M
Vref =  0.0V
C_comp   4.200pF   3.800pF   7.500pF
[Temperature Range]   25.000   0.105k   -40.000
[Voltage Range]   1.500V   1.430V   1.580V
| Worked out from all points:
|   slope of the pulldown table from 0 to 0.225 V, typ, clamps not added: 20.4 ohm
|   slope of the pullup table from 0 to 0.225 V, typ, clamps not added: 23.3 ohm
|   GND clamp passes 1 mA (typ) near -0.44 V on its own axis
|   POWER clamp passes 1 mA (typ) near -0.54 V on its own axis
|   rising waveform, R_fixture 50.000, V_fixture 0.0: 20-80 % time 383ps typ, 523ps min, 170ps max; typ from 0 V to 0.9 V
|   rising waveform, R_fixture 50.000, V_fixture 1.500: 20-80 % time 239ps typ, 413ps min, 114ps max; typ from 0.529 V to 1.5 V
|   falling waveform, R_fixture 50.000, V_fixture 1.500: 20-80 % time 303ps typ, 470ps min, 166ps max; typ from 1.5 V to 0.528 V
|   falling waveform, R_fixture 50.000, V_fixture 0.0: 20-80 % time 212ps typ, 376ps min, 105ps max; typ from 0.9 V to 0 V
[Pulldown]
|Voltage   I(typ)   I(min)   I(max)
-1.5V     -38.2mA    -21.99mA   -59.93mA
-856mV    -38.2mA    -21.99mA   -59.93mA
-580mV    -33.29mA   -21.45mA   -51.12mA
-396mV    -24.09mA   -14.99mA   -38.38mA
156mV     8.127mA    4.623mA    13.97mA
294mV     13.59mA    7.677mA    23.37mA
478mV     18.49mA    10.34mA    31.68mA
938mV     22.73mA    12.61mA    38.32mA
1.95V     24.84mA    13.99mA    41.43mA
2.364V    29.33mA    18.99mA    43.02mA
2.64V     37.25mA    25.21mA    53.09mA
3V        51.32mA    35.47mA    73.31mA
[Pullup]
|Voltage   I(typ)   I(min)   I(max)
-1.5V     106.8mA    77.18mA    169.3mA
-1.186V   82.13mA    59.24mA    129.4mA
-956mV    64.9mA     46.45mA    102.2mA
-542mV    35.44mA    24.73mA    57.94mA
-174mV    9.761mA    6.692mA    16.69mA
-36mV     1.872mA    1.261mA    3.264mA
102mV     -4.819mA   -3.211mA   -8.515mA
240mV     -10.16mA   -6.718mA   -18.18mA
378mV     -14.18mA   -9.28mA    -25.75mA
608mV     -18.05mA   -11.55mA   -33.86mA
838mV     -19.2mA    -12.1mA    -37.04mA
3V        -22.36mA   -13.9mA    -44.21mA
[GND_clamp]
|Voltage   I(typ)   I(min)   I(max)
-1.5V     -1.124A    -960.6mA   -1.411A
-1.097V   -411.6mA   -430.5mA   -392.9mA
-1.066V   -360.7mA   -392.1mA   -323mA
-1.035V   -311mA     -354.2mA   -256.7mA
-973mV    -216.8mA   -280.8mA   -144.3mA
-942mV    -173.5mA   -245.5mA   -105.7mA
-849mV    -71.06mA   -147.7mA   -64.61mA
-787mV    -39.17mA   -92.07mA   -53.7mA
-725mV    -26.41mA   -48.02mA   -41.6mA
-601mV    -11.16mA   -7.552mA   -18.74mA
-384mV    -258.6uA   -114.9uA   -396.2uA
1.5V      -41.68nA   0A         -8.283uA
[POWER_clamp]
|Voltage   I(typ)   I(min)   I(max)
-1.5V     16.13mA    9.435mA    32.38mA
-1.135V   10.69mA    6.084mA    22.87mA
-887mV    6.888mA    3.813mA    15.95mA
-794mV    5.406mA    2.992mA    12.8mA
-763mV    4.897mA    2.724mA    11.46mA
-639mV    2.697mA    1.677mA    5.367mA
-577mV    1.529mA    1.181mA    2.962mA
-515mV    656.7uA    722.8uA    1.279mA
-453mV    227.4uA    343.3uA    403.8uA
-391mV    80.76uA    114.4uA    122.7uA
-267mV    21.1uA     15.5uA     34.42uA
1.5V      0A         0A         0A
[Ramp]
| variable   typ   min   max
dV/dt_r   0.540/0.379n   0.363/0.518n   0.736/0.171n
dV/dt_f   0.583/0.294n   0.369/0.471n   0.754/0.166n
R_load = 50.000
[Rising Waveform]
R_fixture= 50.000
V_fixture= 0.0
V_fixture_min= 0.0
V_fixture_max= 0.0
|time   V(typ)   V(min)   V(max)
0s        304.8uV    218.6uV    443.3uV
805ps     325.5uV    222.9uV    -35.78mV
977ps     399.4uV    222.9uV    767.7mV
1.075ns   164.7uV    222.9uV    1.032V
1.641ns   31.45mV    352.4uV    1.206V
2.074ns   710.8mV    -190.6uV   1.22V
2.95ns    867.9mV    -12.65mV   1.226V
3.624ns   887.8mV    480.4mV    1.227V
4.64ns    896.9mV    576.9mV    1.227V
20ns      899.9mV    604.9mV    1.227V
[Rising Waveform]
R_fixture= 50.000
V_fixture= 1.500
V_fixture_min= 1.430
V_fixture_max= 1.580
|time   V(typ)   V(min)   V(max)
0s        528.5mV    815.7mV    324.1mV
727ps     528.5mV    815.7mV    324.3mV
942ps     528.6mV    815.7mV    1.412V
1.188ns   525.6mV    815.7mV    1.556V
1.408ns   565.7mV    815.5mV    1.568V
1.766ns   1.381V     816mV      1.575V
2.096ns   1.482V     814.1mV    1.578V
3.102ns   1.497V     1.353V     1.58V
3.66ns    1.499V     1.422V     1.58V
20ns      1.5V       1.43V      1.58V
[Falling Waveform]
R_fixture= 50.000
V_fixture= 1.500
V_fixture_min= 1.430
V_fixture_max= 1.580
|time   V(typ)   V(min)   V(max)
0s        1.5V       1.43V      1.58V
830ps     1.5V       1.43V      1.637V
1.108ns   1.5V       1.43V      493.8mV
1.564ns   1.546V     1.43V      341.1mV
2.074ns   718.3mV    1.43V      329.1mV
2.648ns   554.5mV    1.431V     325.1mV
3.118ns   539.2mV    1.463V     324.4mV
3.691ns   532.7mV    972.1mV    324.1mV
4.638ns   529.5mV    833.1mV    324.2mV
20ns      528.4mV    815.7mV    324.1mV
[Falling Waveform]
R_fixture= 50.000
V_fixture= 0.0
V_fixture_min= 0.0
V_fixture_max= 0.0
|time   V(typ)   V(min)   V(max)
0s        899.9mV    604.9mV    1.227V
772ps     900mV      605mV      1.22V
969ps     899.9mV    605mV      153.3mV
1.272ns   898.9mV    605mV      15.71mV
1.504ns   856.4mV    605mV      7.917mV
1.835ns   100.8mV    605mV      3.552mV
2.327ns   9.077mV    603.5mV    1.233mV
3.331ns   1.93mV     66.07mV    516.7uV
3.904ns   846.3uV    6.713mV    477uV
20ns      304.3uV    218.6uV    442.8uV
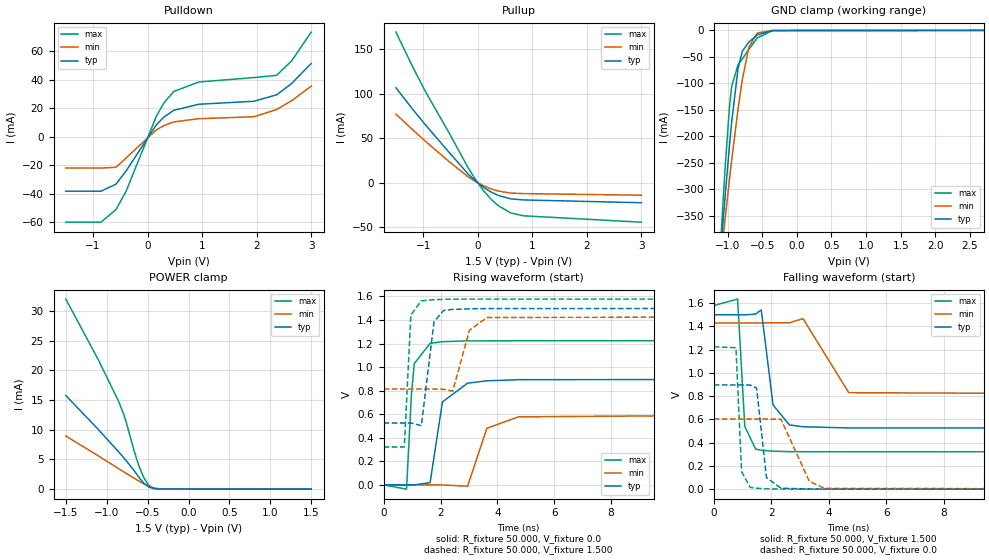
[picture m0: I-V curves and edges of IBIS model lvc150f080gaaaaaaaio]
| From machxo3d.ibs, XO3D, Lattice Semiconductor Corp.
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|   Model lvc150f080gaaaaaaaio
[Model] lvc150f080gaaaaaaaio
Model_type I/O
Polarity   Non-Inverting
Enable   Active-Low
Vinl =  0.375V
Vinh =  1.125V
Vmeas =  0.750V
Cref =  0.0F
Rref =  1.000M
Vref =  0.0V
C_comp   4.200pF   3.800pF   7.500pF
[Temperature Range]   25.000   0.105k   -40.000
[Voltage Range]   1.500V   1.430V   1.580V
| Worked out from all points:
|   slope of the pulldown table from 0 to 0.225 V, typ, clamps not added: 20.4 ohm
|   slope of the pullup table from 0 to 0.225 V, typ, clamps not added: 23.3 ohm
|   GND clamp passes 1 mA (typ) near -0.43 V on its own axis
|   POWER clamp passes 1 mA (typ) near -0.55 V on its own axis
|   rising waveform, R_fixture 50.000, V_fixture 0.0: 20-80 % time 387ps typ, 514ps min, 170ps max; typ from 0 V to 0.896 V
|   rising waveform, R_fixture 50.000, V_fixture 1.500: 20-80 % time 240ps typ, 415ps min, 114ps max; typ from 0.526 V to 1.5 V
|   falling waveform, R_fixture 50.000, V_fixture 1.500: 20-80 % time 300ps typ, 472ps min, 164ps max; typ from 1.5 V to 0.526 V
|   falling waveform, R_fixture 50.000, V_fixture 0.0: 20-80 % time 211ps typ, 372ps min, 105ps max; typ from 0.896 V to 0 V
[Pulldown]
|Voltage   I(typ)   I(min)   I(max)
-1.5V     -38.2mA    -21.99mA   -59.93mA
-856mV    -38.2mA    -21.99mA   -59.93mA
-580mV    -33.29mA   -21.45mA   -51.12mA
-396mV    -24.09mA   -14.99mA   -38.38mA
156mV     8.127mA    4.623mA    13.97mA
294mV     13.59mA    7.677mA    23.37mA
478mV     18.49mA    10.34mA    31.68mA
938mV     22.73mA    12.61mA    38.32mA
1.95V     24.84mA    13.99mA    41.43mA
2.364V    29.33mA    18.99mA    42.98mA
2.64V     37.26mA    25.2mA     53.08mA
3V        51.32mA    35.46mA    73.31mA
[Pullup]
|Voltage   I(typ)   I(min)   I(max)
-1.5V     106.8mA    77.16mA    169.3mA
-1.186V   82.13mA    59.23mA    129.4mA
-956mV    64.9mA     46.45mA    102.2mA
-542mV    35.45mA    24.73mA    57.94mA
-174mV    9.761mA    6.692mA    16.69mA
-36mV     1.872mA    1.261mA    3.264mA
102mV     -4.819mA   -3.211mA   -8.515mA
240mV     -10.16mA   -6.718mA   -18.18mA
378mV     -14.18mA   -9.28mA    -25.75mA
608mV     -18.05mA   -11.55mA   -33.86mA
838mV     -19.2mA    -12.1mA    -37.04mA
3V        -22.36mA   -13.9mA    -44.21mA
[GND_clamp]
|Voltage   I(typ)   I(min)   I(max)
-1.5V     -1.124A    -960.6mA   -1.411A
-1.097V   -411.6mA   -430.5mA   -393mA
-1.066V   -360.7mA   -392.1mA   -323mA
-1.035V   -311mA     -354.2mA   -256.8mA
-973mV    -216.9mA   -280.8mA   -144.3mA
-942mV    -173.5mA   -245.5mA   -105.7mA
-849mV    -71.09mA   -147.7mA   -64.66mA
-787mV    -39.21mA   -92.09mA   -53.75mA
-694mV    -22.05mA   -31.84mA   -35.55mA
-570mV    -8.285mA   -4.678mA   -14.06mA
-353mV    -178.3uA   -91.12uA   -279.1uA
3V        108.1uA    41.24uA    254.4uA
[POWER_clamp]
|Voltage   I(typ)   I(min)   I(max)
-1.5V     15.78mA    8.958mA    32.02mA
-1.104V   10.07mA    5.622mA    21.83mA
-856mV    6.305mA    3.46mA     14.84mA
-794mV    5.324mA    2.93mA     12.69mA
-763mV    4.82mA     2.667mA    11.36mA
-670mV    3.216mA    1.891mA    6.697mA
-608mV    2.042mA    1.391mA    3.973mA
-546mV    979.4uA    916.1uA    1.9mA
-484mV    340.1uA    494.4uA    627.5uA
-422mV    90.48uA    185.7uA    125.7uA
-329mV    10.53uA    21.57uA    6.907uA
1.5V      0A         0A         -3.95nA
[Ramp]
| variable   typ   min   max
dV/dt_r   0.538/0.379n   0.362/0.518n   0.734/0.171n
dV/dt_f   0.584/0.292n   0.369/0.469n   0.754/0.165n
R_load = 50.000
[Rising Waveform]
R_fixture= 50.000
V_fixture= 0.0
V_fixture_min= 0.0
V_fixture_max= 0.0
|time   V(typ)   V(min)   V(max)
0s        2.856nV    35.01nV    1.357nV
805ps     20.22uV    28.73uV    -36.47mV
977ps     73.92uV    3.732uV    764.9mV
1.076ns   -197.4uV   3.732uV    1.029V
1.634ns   19.22mV    136.8uV    1.202V
2.068ns   704.2mV    -407.4uV   1.216V
2.954ns   864mV      -11.43mV   1.223V
3.63ns    883.9mV    480.7mV    1.223V
4.749ns   893.4mV    577.8mV    1.224V
20ns      896mV      602.8mV    1.224V
[Rising Waveform]
R_fixture= 50.000
V_fixture= 1.500
V_fixture_min= 1.430
V_fixture_max= 1.580
|time   V(typ)   V(min)   V(max)
0s        525.6mV    813.6mV    321.6mV
727ps     525.6mV    813.6mV    321.6mV
957ps     525.7mV    813.6mV    1.443V
1.326ns   502.8mV    813.5mV    1.563V
1.771ns   1.384V     813.9mV    1.573V
2.107ns   1.481V     811.3mV    1.576V
2.431ns   1.49V      796.2mV    1.577V
3.017ns   1.495V     1.313V     1.578V
3.634ns   1.497V     1.421V     1.578V
20ns      1.499V     1.429V     1.578V
[Falling Waveform]
R_fixture= 50.000
V_fixture= 1.500
V_fixture_min= 1.430
V_fixture_max= 1.580
|time   V(typ)   V(min)   V(max)
0s        1.499V     1.429V     1.578V
829ps     1.499V     1.429V     1.634V
1.079ns   1.498V     1.429V     539.8mV
1.455ns   1.505V     1.429V     344.9mV
1.653ns   1.54V      1.429V     334.7mV
2.062ns   724.3mV    1.43V      326.6mV
2.632ns   552.1mV    1.43V      322.5mV
3.105ns   536.4mV    1.466V     321.9mV
4.697ns   526.3mV    829.5mV    321.6mV
20ns      525.5mV    813.6mV    321.6mV
[Falling Waveform]
R_fixture= 50.000
V_fixture= 0.0
V_fixture_min= 0.0
V_fixture_max= 0.0
|time   V(typ)   V(min)   V(max)
0s        896mV      602.8mV    1.224V
772ps     896mV      602.8mV    1.216V
968ps     896mV      602.8mV    151.1mV
1.266ns   895.1mV    602.8mV    15.06mV
1.49ns    868.8mV    602.8mV    7.964mV
1.834ns   99.33mV    602.8mV    3.042mV
2.337ns   8.214mV    601.3mV    766.9uV
3.326ns   1.587mV    66.98mV    67.44uV
3.853ns   684.4uV    7.165mV    30.13uV
20ns      -95.6nV    -193.4nV   -434.6nV
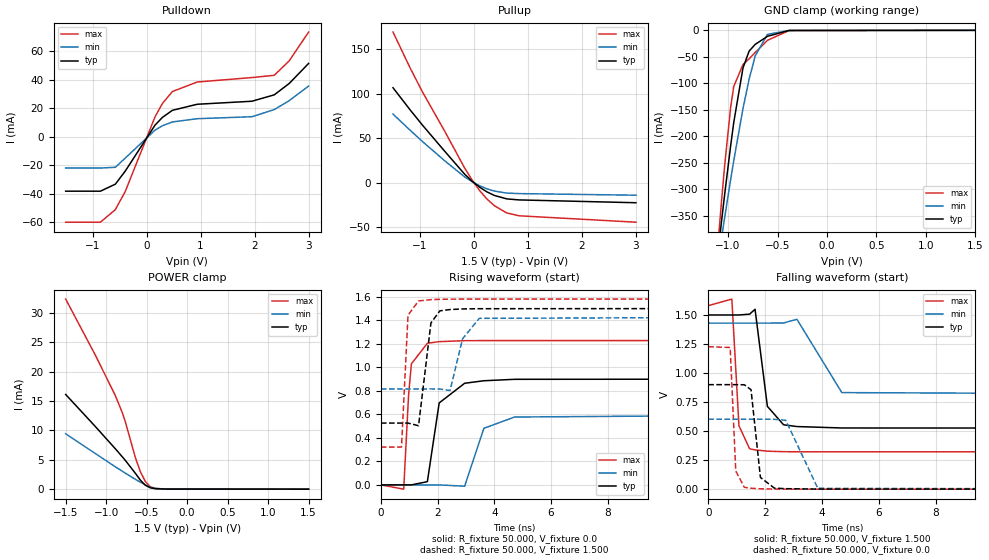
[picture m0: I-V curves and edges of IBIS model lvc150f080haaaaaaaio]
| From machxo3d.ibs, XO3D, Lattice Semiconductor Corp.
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|   Model lvc150f080haaaaaaaio
[Model] lvc150f080haaaaaaaio
Model_type I/O
Polarity   Non-Inverting
Enable   Active-Low
Vinl =  0.375V
Vinh =  1.125V
Vmeas =  0.750V
Cref =  0.0F
Rref =  1.000M
Vref =  0.0V
C_comp   4.200pF   3.800pF   7.500pF
[Temperature Range]   25.000   0.105k   -40.000
[Voltage Range]   1.500V   1.430V   1.580V
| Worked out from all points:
|   slope of the pulldown table from 0 to 0.225 V, typ, clamps not added: 20.4 ohm
|   slope of the pullup table from 0 to 0.225 V, typ, clamps not added: 23.3 ohm
|   GND clamp passes 1 mA (typ) near -0.43 V on its own axis
|   POWER clamp passes 1 mA (typ) near -0.54 V on its own axis
|   rising waveform, R_fixture 50.000, V_fixture 0.0: 20-80 % time 391ps typ, 513ps min, 172ps max; typ from 0 V to 0.9 V
|   rising waveform, R_fixture 50.000, V_fixture 1.500: 20-80 % time 240ps typ, 415ps min, 114ps max; typ from 0.526 V to 1.5 V
|   falling waveform, R_fixture 50.000, V_fixture 1.500: 20-80 % time 306ps typ, 470ps min, 167ps max; typ from 1.5 V to 0.526 V
|   falling waveform, R_fixture 50.000, V_fixture 0.0: 20-80 % time 212ps typ, 375ps min, 105ps max; typ from 0.9 V to 0 V
[Pulldown]
|Voltage   I(typ)   I(min)   I(max)
-1.5V     -38.2mA    -21.99mA   -59.93mA
-856mV    -38.2mA    -21.99mA   -59.93mA
-580mV    -33.29mA   -21.45mA   -51.12mA
-396mV    -24.09mA   -14.99mA   -38.38mA
156mV     8.127mA    4.623mA    13.97mA
294mV     13.59mA    7.677mA    23.37mA
478mV     18.49mA    10.34mA    31.68mA
938mV     22.73mA    12.61mA    38.32mA
1.95V     24.84mA    13.99mA    41.43mA
2.364V    29.33mA    18.99mA    43.02mA
2.64V     37.25mA    25.21mA    53.09mA
3V        51.32mA    35.47mA    73.31mA
[Pullup]
|Voltage   I(typ)   I(min)   I(max)
-1.5V     106.8mA    77.18mA    169.3mA
-1.186V   82.13mA    59.24mA    129.4mA
-956mV    64.9mA     46.45mA    102.2mA
-542mV    35.44mA    24.73mA    57.94mA
-174mV    9.761mA    6.692mA    16.69mA
-36mV     1.872mA    1.261mA    3.264mA
102mV     -4.819mA   -3.211mA   -8.515mA
240mV     -10.16mA   -6.718mA   -18.18mA
378mV     -14.18mA   -9.28mA    -25.75mA
608mV     -18.05mA   -11.55mA   -33.86mA
838mV     -19.2mA    -12.1mA    -37.04mA
3V        -22.36mA   -13.9mA    -44.21mA
[GND_clamp]
|Voltage   I(typ)   I(min)   I(max)
-1.5V     -1.124A    -960.6mA   -1.411A
-1.097V   -411.6mA   -430.5mA   -393mA
-1.066V   -360.7mA   -392.1mA   -323mA
-1.035V   -311mA     -354.2mA   -256.8mA
-973mV    -216.9mA   -280.8mA   -144.3mA
-942mV    -173.5mA   -245.5mA   -105.7mA
-849mV    -71.09mA   -147.7mA   -64.66mA
-787mV    -39.21mA   -92.09mA   -53.75mA
-725mV    -26.45mA   -48.04mA   -41.65mA
-601mV    -11.21mA   -7.588mA   -18.81mA
-384mV    -319.8uA   -151.2uA   -484.4uA
1.5V      -41.68nA   0A         -8.283uA
[POWER_clamp]
|Voltage   I(typ)   I(min)   I(max)
-1.5V     16.13mA    9.435mA    32.38mA
-1.135V   10.69mA    6.084mA    22.87mA
-887mV    6.888mA    3.813mA    15.95mA
-794mV    5.406mA    2.992mA    12.8mA
-763mV    4.897mA    2.724mA    11.46mA
-639mV    2.697mA    1.677mA    5.367mA
-577mV    1.529mA    1.181mA    2.962mA
-515mV    656.7uA    722.8uA    1.279mA
-453mV    227.4uA    343.3uA    403.8uA
-391mV    80.76uA    114.4uA    122.7uA
-267mV    21.1uA     15.5uA     34.42uA
1.5V      0A         0A         0A
[Ramp]
| variable   typ   min   max
dV/dt_r   0.540/0.385n   0.362/0.518n   0.736/0.173n
dV/dt_f   0.585/0.297n   0.369/0.471n   0.755/0.167n
R_load = 50.000
[Rising Waveform]
R_fixture= 50.000
V_fixture= 0.0
V_fixture_min= 0.0
V_fixture_max= 0.0
|time   V(typ)   V(min)   V(max)
0s        2.856nV    35.01nV    1.357nV
805ps     20.22uV    28.7uV     -36.47mV
977ps     76.36uV    3.705uV    764.9mV
1.076ns   -187.5uV   3.705uV    1.029V
1.639ns   27.43mV    136.7uV    1.204V
2.056ns   696.9mV    -407.4uV   1.218V
2.954ns   864mV      -11.43mV   1.226V
3.63ns    885.4mV    480.7mV    1.227V
4.711ns   897.6mV    576.8mV    1.227V
20ns      899.9mV    602.8mV    1.227V
[Rising Waveform]
R_fixture= 50.000
V_fixture= 1.500
V_fixture_min= 1.430
V_fixture_max= 1.580
|time   V(typ)   V(min)   V(max)
0s        525.6mV    815.7mV    321.6mV
727ps     525.6mV    815.7mV    321.6mV
957ps     525.7mV    815.7mV    1.443V
1.328ns   503.1mV    815.5mV    1.564V
1.765ns   1.377V     816mV      1.575V
2.08ns    1.48V      815.2mV    1.578V
2.44ns    1.491V     802.1mV    1.579V
2.878ns   1.496V     1.241V     1.58V
3.468ns   1.498V     1.416V     1.58V
20ns      1.5V       1.43V      1.58V
[Falling Waveform]
R_fixture= 50.000
V_fixture= 1.500
V_fixture_min= 1.430
V_fixture_max= 1.580
|time   V(typ)   V(min)   V(max)
0s        1.5V       1.43V      1.58V
830ps     1.5V       1.43V      1.637V
1.08ns    1.5V       1.43V      545.6mV
1.454ns   1.507V     1.43V      348.1mV
1.646ns   1.549V     1.43V      338.4mV
2.08ns    713mV      1.43V      327mV
2.648ns   554.5mV    1.431V     322.8mV
3.118ns   539.2mV    1.463V     322mV
4.697ns   526.9mV    831.6mV    321.6mV
20ns      525.5mV    815.7mV    321.6mV
[Falling Waveform]
R_fixture= 50.000
V_fixture= 0.0
V_fixture_min= 0.0
V_fixture_max= 0.0
|time   V(typ)   V(min)   V(max)
0s        899.9mV    602.8mV    1.227V
772ps     900mV      602.8mV    1.22V
968ps     899.9mV    602.8mV    156mV
1.27ns    898.9mV    602.8mV    15.85mV
1.504ns   856.4mV    602.8mV    8.011mV
1.835ns   100.8mV    602.8mV    3.168mV
2.326ns   9.106mV    601.3mV    810.1uV
2.725ns   4.194mV    593.3mV    338.5uV
3.853ns   698.4uV    7.165mV    32.9uV
20ns      -189.4nV   -194nV     -308.2nV
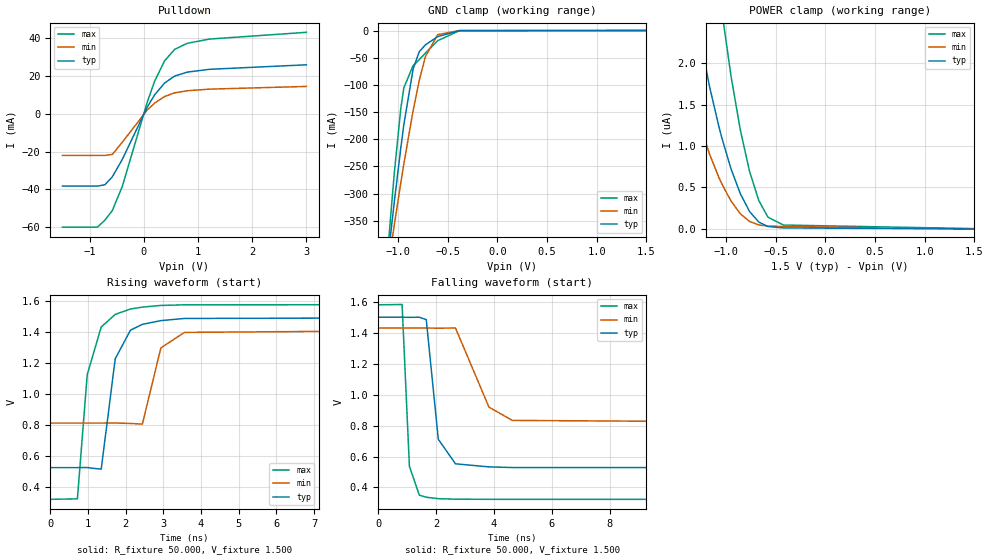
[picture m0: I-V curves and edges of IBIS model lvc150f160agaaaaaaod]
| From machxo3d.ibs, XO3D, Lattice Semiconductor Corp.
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|   Model lvc150f160agaaaaaaod
[Model] lvc150f160agaaaaaaod
Model_type I/O_open_drain
Polarity   Non-Inverting
Enable   Active-Low
Vinl =  0.375V
Vinh =  1.125V
Vmeas =  0.750V
Cref =  0.0F
Rref = 10.00k
Vref = 1.50V
C_comp   4.200pF   3.800pF   7.500pF
[Temperature Range]   25.000   0.105k   -40.000
[Voltage Range]   1.500V   1.430V   1.580V
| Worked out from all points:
|   slope of the pulldown table from 0 to 0.225 V, typ, clamps not added: 20.4 ohm
|   GND clamp passes 1 mA (typ) near -0.44 V on its own axis
|   rising waveform, R_fixture 50.000, V_fixture 1.500: 20-80 % time 351ps typ, 372ps min, 353ps max; typ from 0.528 V to 1.5 V
|   falling waveform, R_fixture 50.000, V_fixture 1.500: 20-80 % time 315ps typ, 486ps min, 170ps max; typ from 1.5 V to 0.528 V
[Pulldown]
|Voltage   I(typ)   I(min)   I(max)
-1.5V     -38.2mA    -21.99mA   -59.93mA
-856mV    -38.2mA    -21.99mA   -59.93mA
-718mV    -37.5mA    -21.99mA   -56.26mA
-580mV    -33.29mA   -21.45mA   -51.12mA
-396mV    -24.09mA   -14.99mA   -38.38mA
64mV      3.591mA    2.051mA    6.169mA
202mV     10.12mA    5.747mA    17.41mA
386mV     16.37mA    9.198mA    28.13mA
570mV     20.01mA    11.14mA    34.13mA
800mV     22.07mA    12.24mA    37.32mA
1.214V    23.58mA    13.09mA    39.59mA
3V        25.97mA    14.52mA    43.15mA
[GND_clamp]
|Voltage   I(typ)   I(min)   I(max)
-1.5V     -1.124A    -960.6mA   -1.411A
-1.097V   -411.6mA   -430.5mA   -392.9mA
-1.066V   -360.7mA   -392.1mA   -323mA
-1.035V   -311mA     -354.2mA   -256.7mA
-973mV    -216.8mA   -280.8mA   -144.2mA
-942mV    -173.4mA   -245.5mA   -105.6mA
-849mV    -71.05mA   -147.7mA   -64.59mA
-787mV    -39.16mA   -92.07mA   -53.68mA
-725mV    -26.4mA    -48.02mA   -41.58mA
-601mV    -11.15mA   -7.544mA   -18.72mA
-384mV    -236.4uA   -103.3uA   -351.1uA
1.5V      0A         0A         0A
[POWER_clamp]
|Voltage   I(typ)   I(min)   I(max)
-1.5V     4.017uA    2.297uA    8.486uA
-1.321V   2.676uA    1.475uA    5.815uA
-1.166V   1.719uA    902.9nA    3.892uA
-1.073V   1.242uA    625.4nA    2.92uA
-1.042V   1.099uA    544.2nA    2.626uA
-949mV    723.1nA    335.9nA    1.84uA
-856mV    425.6nA    184nA      1.196uA
-763mV    211.2nA    90.94nA    695.6nA
-670mV    83.05nA    48.41nA    343.1nA
-577mV    29.4nA     34.61nA    141.1nA
-422mV    12.85nA    29.5nA     47.32nA
1.5V      0A         0A         4.131nA
[Ramp]
| variable   typ   min   max
dV/dt_r   0.583/0.349n   0.369/0.371n   0.754/0.353n
dV/dt_f   0.583/0.313n   0.369/0.484n   0.754/0.169n
R_load = 50.000
[Rising Waveform]
R_fixture= 50.000
V_fixture= 1.500
V_fixture_min= 1.430
V_fixture_max= 1.580
|time   V(typ)   V(min)   V(max)
0s        527.9mV    815.2mV    323.4mV
720ps     527.9mV    815.2mV    326.4mV
981ps     528.4mV    815.2mV    1.128V
1.352ns   517.8mV    815.1mV    1.435V
1.724ns   1.23V      815.7mV    1.516V
2.127ns   1.414V     812.7mV    1.551V
2.444ns   1.452V     808.8mV    1.563V
2.935ns   1.476V     1.3V       1.574V
3.56ns    1.49V      1.4V       1.578V
20ns      1.5V       1.43V      1.58V
[Falling Waveform]
R_fixture= 50.000
V_fixture= 1.500
V_fixture_min= 1.430
V_fixture_max= 1.580
|time   V(typ)   V(min)   V(max)
0s        1.5V       1.43V      1.58V
825ps     1.5V       1.43V      1.582V
1.078ns   1.499V     1.43V      537mV
1.42ns    1.5V       1.43V      350.4mV
1.66ns    1.484V     1.43V      336.9mV
2.076ns   711.2mV    1.429V     327.7mV
2.669ns   552.9mV    1.43V      324.3mV
3.825ns   532.9mV    919.1mV    323.5mV
4.632ns   528.9mV    833.3mV    323.4mV
20ns      527.7mV    815.2mV    323.4mV
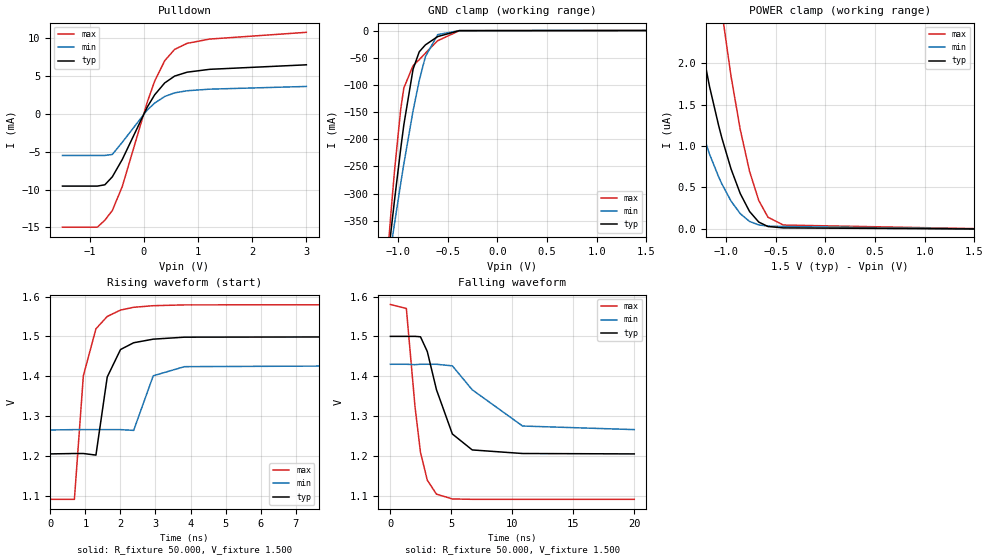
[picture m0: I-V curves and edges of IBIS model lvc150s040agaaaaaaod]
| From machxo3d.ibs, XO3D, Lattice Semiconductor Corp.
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|   Model lvc150s040agaaaaaaod
[Model] lvc150s040agaaaaaaod
Model_type I/O_open_drain
Polarity   Non-Inverting
Enable   Active-Low
Vinl =  0.375V
Vinh =  1.125V
Vmeas =  0.750V
Cref =  0.0F
Rref = 10.00k
Vref = 1.50V
C_comp   4.200pF   3.800pF   7.500pF
[Temperature Range]   25.000   0.105k   -40.000
[Voltage Range]   1.500V   1.430V   1.580V
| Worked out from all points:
|   slope of the pulldown table from 0 to 0.225 V, typ, clamps not added: 81.5 ohm
|   GND clamp passes 1 mA (typ) near -0.44 V on its own axis
|   rising waveform, R_fixture 50.000, V_fixture 1.500: 20-80 % time 354ps typ, 375ps min, 354ps max; typ from 1.21 V to 1.5 V
|   falling waveform, R_fixture 50.000, V_fixture 1.500: 20-80 % time 1.75ns typ, 2.95ns min, 985ps max; typ from 1.5 V to 1.21 V
[Pulldown]
|Voltage   I(typ)   I(min)   I(max)
-1.5V     -9.549mA   -5.496mA   -14.98mA
-856mV    -9.549mA   -5.496mA   -14.98mA
-718mV    -9.375mA   -5.496mA   -14.06mA
-580mV    -8.322mA   -5.363mA   -12.78mA
-396mV    -6.022mA   -3.748mA   -9.594mA
64mV      897.8uA    512.6uA    1.542mA
202mV     2.531mA    1.437mA    4.351mA
386mV     4.093mA    2.3mA      7.031mA
570mV     5.004mA    2.786mA    8.534mA
800mV     5.518mA    3.061mA    9.331mA
1.214V    5.895mA    3.272mA    9.897mA
3V        6.493mA    3.63mA     10.79mA
[GND_clamp]
|Voltage   I(typ)   I(min)   I(max)
-1.5V     -1.124A    -960.6mA   -1.411A
-1.097V   -411.6mA   -430.5mA   -392.9mA
-1.066V   -360.7mA   -392.1mA   -323mA
-1.035V   -311mA     -354.2mA   -256.8mA
-973mV    -216.9mA   -280.8mA   -144.3mA
-942mV    -173.5mA   -245.5mA   -105.7mA
-849mV    -71.07mA   -147.7mA   -64.62mA
-787mV    -39.18mA   -92.07mA   -53.7mA
-725mV    -26.42mA   -48.02mA   -41.6mA
-601mV    -11.16mA   -7.547mA   -18.74mA
-384mV    -237.5uA   -103.4uA   -356uA
1.5V      0A         0A         0A
[POWER_clamp]
|Voltage   I(typ)   I(min)   I(max)
-1.5V     4.017uA    2.297uA    8.486uA
-1.321V   2.676uA    1.475uA    5.815uA
-1.166V   1.719uA    902.9nA    3.892uA
-1.073V   1.242uA    625.4nA    2.92uA
-1.042V   1.099uA    544.2nA    2.626uA
-949mV    723.1nA    335.9nA    1.84uA
-856mV    425.6nA    184nA      1.196uA
-763mV    211.1nA    90.97nA    695.5nA
-670mV    83.02nA    48.45nA    343nA
-577mV    29.37nA    34.64nA    141nA
-422mV    12.82nA    29.53nA    47.27nA
1.5V      0A         0A         4.136nA
[Ramp]
| variable   typ   min   max
dV/dt_r   0.177/0.356n   98.704m/0.378n   0.293/0.356n
dV/dt_f   0.177/1.717n   98.685m/2.871n   0.293/0.983n
R_load = 50.000
[Rising Waveform]
R_fixture= 50.000
V_fixture= 1.500
V_fixture_min= 1.430
V_fixture_max= 1.580
|time   V(typ)   V(min)   V(max)
0s        1.205V     1.265V     1.091V
688ps     1.206V     1.266V     1.091V
943ps     1.206V     1.266V     1.401V
1.302ns   1.202V     1.266V     1.519V
1.624ns   1.398V     1.266V     1.55V
2.003ns   1.467V     1.266V     1.566V
2.378ns   1.484V     1.264V     1.573V
2.935ns   1.493V     1.401V     1.577V
3.825ns   1.498V     1.424V     1.579V
20ns      1.5V       1.43V      1.58V
[Falling Waveform]
R_fixture= 50.000
V_fixture= 1.500
V_fixture_min= 1.430
V_fixture_max= 1.580
|time   V(typ)   V(min)   V(max)
0s        1.5V       1.43V      1.58V
1.309ns   1.5V       1.43V      1.57V
2.018ns   1.5V       1.429V     1.324V
2.468ns   1.499V     1.43V      1.209V
3.026ns   1.462V     1.43V      1.139V
3.78ns    1.366V     1.43V      1.104V
5.082ns   1.255V     1.426V     1.092V
6.709ns   1.215V     1.366V     1.091V
10.84ns   1.206V     1.275V     1.091V
20ns      1.205V     1.266V     1.091V
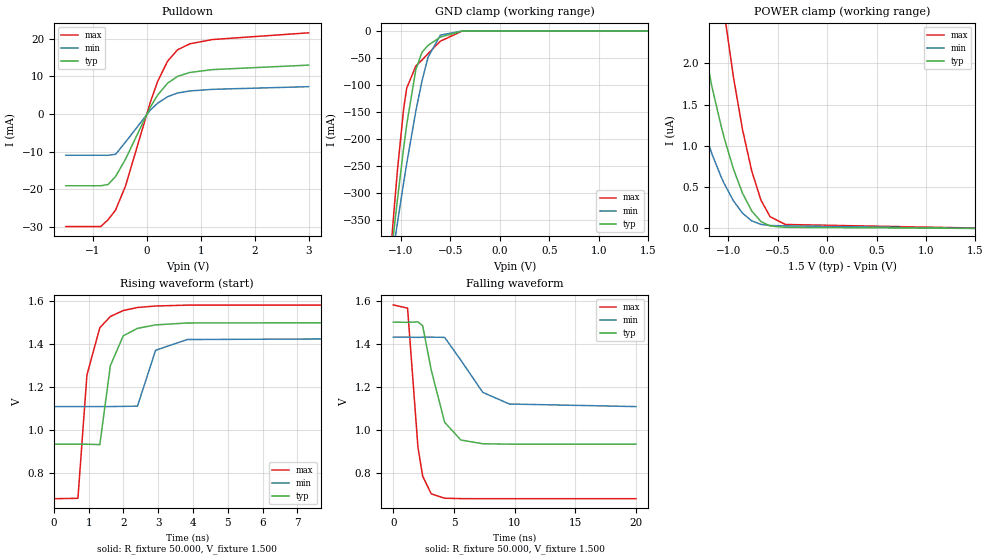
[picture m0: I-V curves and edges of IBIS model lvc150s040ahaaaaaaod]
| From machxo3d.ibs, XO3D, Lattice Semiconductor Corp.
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|   Model lvc150s040ahaaaaaaod
[Model] lvc150s040ahaaaaaaod
Model_type I/O_open_drain
Polarity   Non-Inverting
Enable   Active-Low
Vinl =  0.375V
Vinh =  1.125V
Vmeas =  0.750V
Cref =  0.0F
Rref = 10.00k
Vref = 1.50V
C_comp   4.200pF   3.800pF   7.500pF
[Temperature Range]   25.000   0.105k   -40.000
[Voltage Range]   1.500V   1.430V   1.580V
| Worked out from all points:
|   slope of the pulldown table from 0 to 0.225 V, typ, clamps not added: 40.7 ohm
|   GND clamp passes 1 mA (typ) near -0.44 V on its own axis
|   rising waveform, R_fixture 50.000, V_fixture 1.500: 20-80 % time 351ps typ, 377ps min, 351ps max; typ from 0.932 V to 1.5 V
|   falling waveform, R_fixture 50.000, V_fixture 1.500: 20-80 % time 1.35ns typ, 2.22ns min, 757ps max; typ from 1.5 V to 0.932 V
[Pulldown]
|Voltage   I(typ)   I(min)   I(max)
-1.5V     -19.1mA    -10.99mA   -29.96mA
-856mV    -19.1mA    -10.99mA   -29.96mA
-718mV    -18.75mA   -10.99mA   -28.13mA
-580mV    -16.64mA   -10.73mA   -25.56mA
-396mV    -12.04mA   -7.496mA   -19.19mA
64mV      1.796mA    1.025mA    3.085mA
202mV     5.062mA    2.873mA    8.703mA
386mV     8.187mA    4.599mA    14.06mA
570mV     10.01mA    5.571mA    17.07mA
800mV     11.04mA    6.122mA    18.66mA
1.214V    11.79mA    6.545mA    19.79mA
3V        12.99mA    7.26mA     21.58mA
[GND_clamp]
|Voltage   I(typ)   I(min)   I(max)
-1.5V     -1.124A    -960.6mA   -1.411A
-1.097V   -411.6mA   -430.5mA   -392.9mA
-1.066V   -360.7mA   -392.1mA   -323mA
-1.035V   -311mA     -354.2mA   -256.8mA
-973mV    -216.9mA   -280.8mA   -144.3mA
-942mV    -173.5mA   -245.5mA   -105.7mA
-849mV    -71.07mA   -147.7mA   -64.62mA
-787mV    -39.18mA   -92.07mA   -53.7mA
-725mV    -26.42mA   -48.02mA   -41.6mA
-601mV    -11.16mA   -7.547mA   -18.74mA
-384mV    -237.5uA   -103.4uA   -356uA
1.5V      0A         0A         0A
[POWER_clamp]
|Voltage   I(typ)   I(min)   I(max)
-1.5V     4.017uA    2.297uA    8.486uA
-1.321V   2.676uA    1.475uA    5.815uA
-1.166V   1.719uA    902.9nA    3.892uA
-1.073V   1.242uA    625.4nA    2.92uA
-1.042V   1.099uA    544.2nA    2.626uA
-949mV    723.1nA    335.9nA    1.84uA
-856mV    425.5nA    184nA      1.196uA
-763mV    211.1nA    90.96nA    695.5nA
-670mV    83.02nA    48.44nA    343nA
-577mV    29.37nA    34.64nA    141nA
-422mV    12.82nA    29.53nA    47.26nA
1.5V      0A         0A         4.136nA
[Ramp]
| variable   typ   min   max
dV/dt_r   0.341/0.351n   0.194/0.380n   0.541/0.351n
dV/dt_f   0.341/1.342n   0.194/2.206n   0.541/0.759n
R_load = 50.000
[Rising Waveform]
R_fixture= 50.000
V_fixture= 1.500
V_fixture_min= 1.430
V_fixture_max= 1.580
|time   V(typ)   V(min)   V(max)
0s        932.1mV    1.107V     678.4mV
693ps     932.1mV    1.107V     680.1mV
952ps     932mV      1.107V     1.254V
1.323ns   930mV      1.107V     1.474V
1.625ns   1.297V     1.107V     1.526V
1.995ns   1.436V     1.108V     1.554V
2.405ns   1.471V     1.109V     1.568V
2.926ns   1.487V     1.369V     1.575V
3.837ns   1.496V     1.419V     1.579V
20ns      1.5V       1.43V      1.58V
[Falling Waveform]
R_fixture= 50.000
V_fixture= 1.500
V_fixture_min= 1.430
V_fixture_max= 1.580
|time   V(typ)   V(min)   V(max)
0s        1.5V       1.43V      1.58V
1.175ns   1.499V     1.43V      1.565V
2.031ns   1.501V     1.429V     918.1mV
2.42ns    1.483V     1.43V      783.2mV
3.126ns   1.277V     1.43V      701.1mV
4.23ns    1.034V     1.429V     680.7mV
5.564ns   951.5mV    1.323V     678.8mV
7.378ns   934mV      1.173V     678.4mV
9.564ns   932.2mV    1.119V     678.4mV
20ns      932.1mV    1.107V     678.4mV
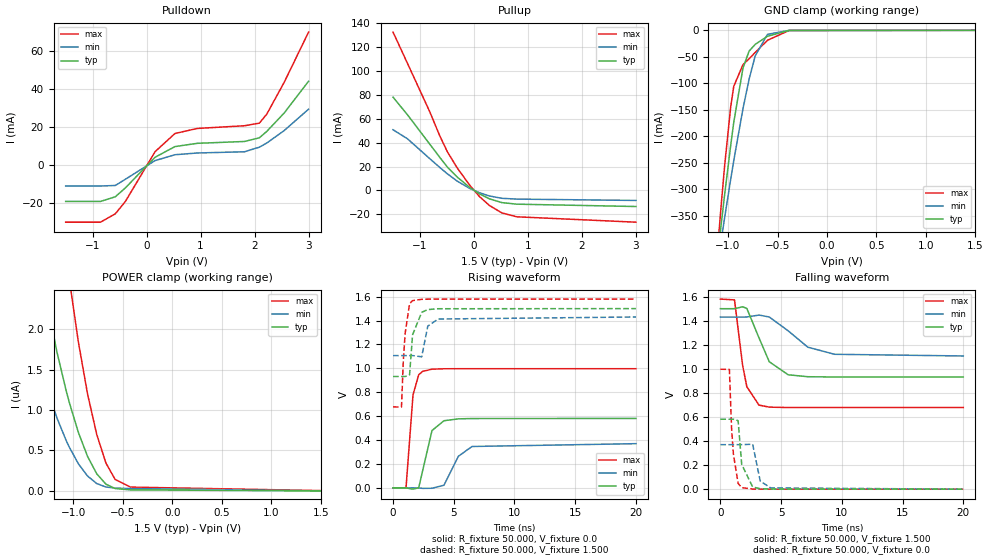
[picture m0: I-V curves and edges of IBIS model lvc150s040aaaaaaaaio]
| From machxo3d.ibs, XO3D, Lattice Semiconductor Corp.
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|   Model lvc150s040aaaaaaaaio
[Model] lvc150s040aaaaaaaaio
Model_type I/O
Polarity   Non-Inverting
Enable   Active-Low
Vinl =  0.375V
Vinh =  1.125V
Vmeas =  0.750V
Cref =  0.0F
Rref =  1.000M
Vref =  0.0V
C_comp   4.200pF   3.800pF   7.500pF
[Temperature Range]   25.000   0.105k   -40.000
[Voltage Range]   1.500V   1.430V   1.580V
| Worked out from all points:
|   slope of the pulldown table from 0 to 0.225 V, typ, clamps not added: 40.7 ohm
|   slope of the pullup table from 0 to 0.225 V, typ, clamps not added: 38.9 ohm
|   GND clamp passes 1 mA (typ) near -0.44 V on its own axis
|   rising waveform, R_fixture 50.000, V_fixture 0.0: 20-80 % time 750ps typ, 1.17ns min, 437ps max; typ from 0 V to 0.581 V
|   rising waveform, R_fixture 50.000, V_fixture 1.500: 20-80 % time 370ps typ, 379ps min, 348ps max; typ from 0.932 V to 1.5 V
|   falling waveform, R_fixture 50.000, V_fixture 1.500: 20-80 % time 1.36ns typ, 2.27ns min, 752ps max; typ from 1.5 V to 0.932 V
|   falling waveform, R_fixture 50.000, V_fixture 0.0: 20-80 % time 386ps typ, 423ps min, 367ps max; typ from 0.581 V to 0 V
[Pulldown]
|Voltage   I(typ)   I(min)   I(max)
-1.5V     -19.1mA    -10.99mA   -29.96mA
-856mV    -19.1mA    -10.99mA   -29.96mA
-580mV    -16.64mA   -10.73mA   -25.56mA
-396mV    -12.04mA   -7.496mA   -19.19mA
156mV     4.064mA    2.312mA    6.984mA
524mV     9.661mA    5.388mA    16.51mA
938mV     11.37mA    6.303mA    19.16mA
1.812V    12.34mA    6.943mA    20.58mA
2.088V    14.25mA    9.352mA    21.95mA
2.226V    17.63mA    11.53mA    26.68mA
2.548V    27.25mA    18.06mA    43.35mA
3V        43.92mA    29.27mA    69.66mA
[Pullup]
|Voltage   I(typ)   I(min)   I(max)
-1.5V     78.01mA    50.76mA    132.4mA
-1.232V   63.25mA    43.2mA     106.2mA
-818mV    38.64mA    26.54mA    65.65mA
-634mV    27.69mA    19.25mA    45.67mA
-496mV    19.72mA    14.01mA    32.57mA
-312mV    11.25mA    7.838mA    18.9mA
-82mV     2.627mA    1.78mA     4.548mA
102mV     -2.891mA   -1.927mA   -5.109mA
286mV     -6.99mA    -4.605mA   -12.56mA
516mV     -10.15mA   -6.555mA   -18.77mA
792mV     -11.45mA   -7.225mA   -22.01mA
3V        -13.42mA   -8.343mA   -26.52mA
[GND_clamp]
|Voltage   I(typ)   I(min)   I(max)
-1.5V     -1.124A    -960.6mA   -1.411A
-1.097V   -411.6mA   -430.5mA   -392.9mA
-1.066V   -360.7mA   -392.1mA   -323mA
-1.035V   -311mA     -354.2mA   -256.7mA
-973mV    -216.8mA   -280.8mA   -144.2mA
-942mV    -173.4mA   -245.5mA   -105.6mA
-849mV    -71.05mA   -147.7mA   -64.59mA
-787mV    -39.16mA   -92.07mA   -53.68mA
-725mV    -26.4mA    -48.02mA   -41.58mA
-601mV    -11.15mA   -7.544mA   -18.72mA
-384mV    -236.4uA   -103.3uA   -351.1uA
1.5V      0A         0A         0A
[POWER_clamp]
|Voltage   I(typ)   I(min)   I(max)
-1.5V     4.017uA    2.297uA    8.486uA
-1.321V   2.676uA    1.475uA    5.815uA
-1.166V   1.719uA    902.9nA    3.892uA
-1.073V   1.242uA    625.4nA    2.92uA
-1.042V   1.099uA    544.2nA    2.626uA
-949mV    723.1nA    335.9nA    1.84uA
-856mV    425.6nA    184nA      1.196uA
-763mV    211.1nA    90.96nA    695.6nA
-670mV    83.03nA    48.44nA    343.1nA
-577mV    29.38nA    34.64nA    141nA
-422mV    12.83nA    29.52nA    47.28nA
1.5V      0A         0A         4.131nA
[Ramp]
| variable   typ   min   max
dV/dt_r   0.349/0.744n   0.222/1.182n   0.598/0.436n
dV/dt_f   0.341/1.345n   0.194/2.219n   0.541/0.758n
R_load = 50.000
[Rising Waveform]
R_fixture= 50.000
V_fixture= 0.0
V_fixture_min= 0.0
V_fixture_max= 0.0
|time   V(typ)   V(min)   V(max)
0s        4.722nV    51.53nV    2.531nV
1.07ns    -41.83uV   6.855uV    1.343mV
1.646ns   -10.61mV   221.9uV    779mV
2.115ns   960.7uV    -717.4uV   946.9mV
2.444ns   146.5mV    -4.103mV   975.1mV
3.208ns   479.9mV    -2.993mV   993.2mV
4.195ns   562.1mV    22.36mV    996.7mV
5.381ns   577.6mV    264.7mV    997.1mV
6.503ns   580.4mV    346.5mV    997.1mV
20ns      581.2mV    370.1mV    997.2mV
[Rising Waveform]
R_fixture= 50.000
V_fixture= 1.500
V_fixture_min= 1.430
V_fixture_max= 1.580
|time   V(typ)   V(min)   V(max)
0s        932.1mV    1.107V     678.4mV
695ps     932.1mV    1.107V     675.4mV
849ps     932mV      1.107V     1.07V
1.003ns   932.1mV    1.107V     1.297V
1.363ns   946.2mV    1.107V     1.541V
1.61ns    1.281V     1.107V     1.567V
2.36ns    1.469V     1.097V     1.578V
2.86ns    1.492V     1.353V     1.579V
3.713ns   1.499V     1.413V     1.58V
20ns      1.5V       1.43V      1.58V
[Falling Waveform]
R_fixture= 50.000
V_fixture= 1.500
V_fixture_min= 1.430
V_fixture_max= 1.580
|time   V(typ)   V(min)   V(max)
0s        1.5V       1.43V      1.58V
1.163ns   1.5V       1.43V      1.573V
1.834ns   1.516V     1.43V      1.027V
2.178ns   1.502V     1.431V     851.4mV
3.178ns   1.258V     1.447V     698.6mV
4.026ns   1.059V     1.431V     681.8mV
5.581ns   950.7mV    1.316V     678.5mV
7.202ns   934.5mV    1.18V      678.4mV
9.401ns   932.3mV    1.121V     678.4mV
20ns      932.1mV    1.107V     678.4mV
[Falling Waveform]
R_fixture= 50.000
V_fixture= 0.0
V_fixture_min= 0.0
V_fixture_max= 0.0
|time   V(typ)   V(min)   V(max)
0s        581.2mV    370.1mV    997.2mV
743ps     581.3mV    370.1mV    994.8mV
919ps     581.3mV    370.1mV    511.1mV
1.072ns   581.3mV    370.1mV    290.8mV
1.461ns   569.1mV    370.1mV    48.31mV
1.754ns   206.9mV    370.1mV    12.66mV
2.659ns   17.78mV    373.6mV    978.4uV
3.282ns   3.95mV     66.85mV    218.3uV
4.148ns   939.7uV    10.44mV    75.33uV
20ns      10.8nV     117.3nV    1.733nV
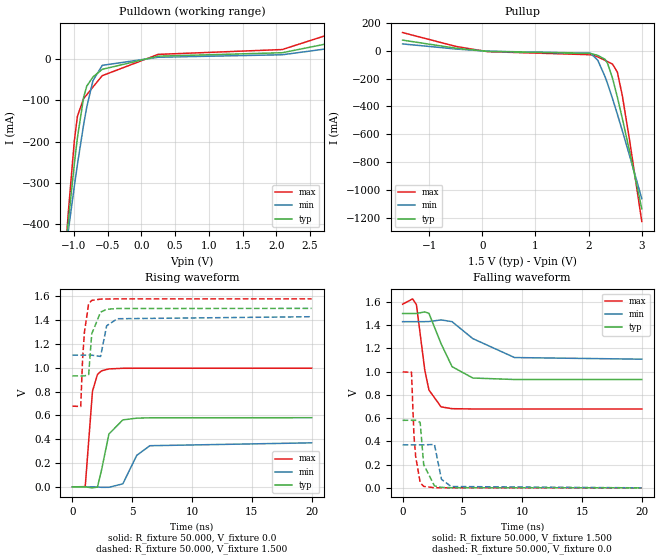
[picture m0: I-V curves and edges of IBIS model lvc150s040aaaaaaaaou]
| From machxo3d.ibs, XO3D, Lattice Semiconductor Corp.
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|   Model lvc150s040aaaaaaaaou
[Model] lvc150s040aaaaaaaaou
Model_type Output
Polarity   Non-Inverting
Enable   Active-High
Vmeas =  0.750V
Cref =  0.0F
Rref =  1.000M
Vref =  0.0V
C_comp   4.200pF   3.800pF   7.500pF
[Temperature Range]   25.000   0.105k   -40.000
[Voltage Range]   1.500V   1.430V   1.580V
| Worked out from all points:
|   slope of the pulldown table from 0 to 0.225 V, typ, clamps not added: 40.7 ohm
|   slope of the pullup table from 0 to 0.225 V, typ, clamps not added: 38.9 ohm
|   rising waveform, R_fixture 50.000, V_fixture 0.0: 20-80 % time 745ps typ, 1.17ns min, 434ps max; typ from 0 V to 0.581 V
|   rising waveform, R_fixture 50.000, V_fixture 1.500: 20-80 % time 366ps typ, 377ps min, 348ps max; typ from 0.932 V to 1.5 V
|   falling waveform, R_fixture 50.000, V_fixture 1.500: 20-80 % time 1.34ns typ, 2.25ns min, 758ps max; typ from 1.5 V to 0.932 V
|   falling waveform, R_fixture 50.000, V_fixture 0.0: 20-80 % time 385ps typ, 417ps min, 372ps max; typ from 0.581 V to 0 V
[Pulldown]
|Voltage   I(typ)   I(min)   I(max)
-1.5V     -1.125A    -961.3mA   -1.413A
-1.132V   -473mA     -476mA     -480.5mA
-1.086V   -396.8mA   -418.5mA   -375.7mA
-994mV    -253.7mA   -307.5mA   -198.1mA
-948mV    -190mA     -254.9mA   -138.6mA
-856mV    -93.02mA   -158.7mA   -95.89mA
-810mV    -66.23mA   -117mA     -87.24mA
-718mV    -44.12mA   -53.14mA   -68.34mA
-580mV    -25.78mA   -16.15mA   -41.02mA
248mV     5.973mA    3.382mA    10.27mA
2.088V    14.25mA    9.352mA    21.95mA
3V        43.92mA    29.27mA    69.66mA
[Pullup]
|Voltage   I(typ)   I(min)   I(max)
-1.5V     78.02mA    50.76mA    132.4mA
-496mV    19.72mA    14.01mA    32.58mA
102mV     -2.891mA   -1.927mA   -5.109mA
2.034V    -17.98mA   -15.79mA   -27.08mA
2.172V    -31.95mA   -66.68mA   -42.37mA
2.31V     -60.53mA   -186.8mA   -67.92mA
2.356V    -89.72mA   -235.8mA   -77.05mA
2.448V    -194.7mA   -341.9mA   -93.98mA
2.54V     -332.1mA   -455mA     -152mA
2.632V    -483.4mA   -572.5mA   -318.5mA
2.77V     -722.8mA   -753.8mA   -641.9mA
3V        -1.137A    -1.064A    -1.229A
[Ramp]
| variable   typ   min   max
dV/dt_r   0.349/0.743n   0.222/1.181n   0.598/0.434n
dV/dt_f   0.341/1.349n   0.194/2.241n   0.541/0.752n
R_load = 50.000
[Rising Waveform]
R_fixture= 50.000
V_fixture= 0.0
V_fixture_min= 0.0
V_fixture_max= 0.0
|time   V(typ)   V(min)   V(max)
0s        4.678nV    51.7nV     2.482nV
1.071ns   -45.51uV   6.134uV    1.769mV
1.68ns    -8.263mV   228.8uV    805mV
2.095ns   -1.722mV   -564.3uV   944.9mV
2.435ns   141.1mV    -4.035mV   974.8mV
3.056ns   445mV      -3.587mV   991.3mV
4.217ns   562.8mV    25.62mV    996.6mV
5.381ns   577.5mV    265.2mV    997mV
6.479ns   580.4mV    345.9mV    997.1mV
20ns      581.2mV    370.1mV    997.2mV
[Rising Waveform]
R_fixture= 50.000
V_fixture= 1.500
V_fixture_min= 1.430
V_fixture_max= 1.580
|time   V(typ)   V(min)   V(max)
0s        932.1mV    1.107V     678.4mV
695ps     932.1mV    1.107V     675.4mV
849ps     932mV      1.107V     1.07V
1.003ns   932.2mV    1.107V     1.298V
1.359ns   943.2mV    1.107V     1.54V
1.616ns   1.286V     1.107V     1.567V
2.356ns   1.469V     1.096V     1.578V
2.865ns   1.492V     1.354V     1.579V
3.75ns    1.499V     1.413V     1.58V
20ns      1.5V       1.43V      1.58V
[Falling Waveform]
R_fixture= 50.000
V_fixture= 1.500
V_fixture_min= 1.430
V_fixture_max= 1.580
|time   V(typ)   V(min)   V(max)
0s        1.5V       1.43V      1.58V
842ps     1.5V       1.43V      1.626V
1.159ns   1.5V       1.43V      1.575V
1.858ns   1.514V     1.43V      1.011V
2.204ns   1.501V     1.431V     841.5mV
3.216ns   1.241V     1.445V     696.8mV
4.134ns   1.043V     1.43V      681.2mV
5.87ns    945mV      1.284V     678.6mV
9.363ns   932.2mV    1.121V     678.4mV
20ns      932.1mV    1.107V     678.4mV
[Falling Waveform]
R_fixture= 50.000
V_fixture= 0.0
V_fixture_min= 0.0
V_fixture_max= 0.0
|time   V(typ)   V(min)   V(max)
0s        581.2mV    370.1mV    997.2mV
743ps     581.3mV    370.1mV    994.8mV
945ps     581.3mV    370.1mV    459.6mV
1.091ns   581.6mV    370.1mV    271.4mV
1.469ns   563.2mV    370.1mV    45.29mV
1.764ns   199.2mV    370.1mV    12.24mV
2.663ns   17.22mV    373.3mV    1.035mV
3.25ns    4.199mV    73.24mV    243.6uV
4.066ns   1.06mV     11.39mV    89.03uV
20ns      12.91nV    113.2nV    35.1nV
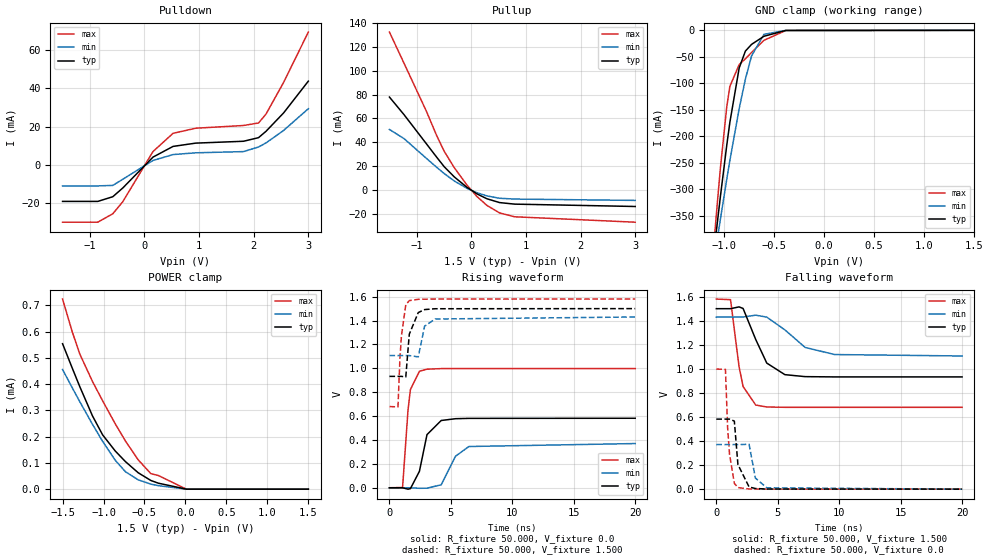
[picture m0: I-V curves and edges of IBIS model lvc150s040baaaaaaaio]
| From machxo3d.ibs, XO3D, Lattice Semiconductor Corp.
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|   Model lvc150s040baaaaaaaio
[Model] lvc150s040baaaaaaaio
Model_type I/O
Polarity   Non-Inverting
Enable   Active-Low
Vinl =  0.375V
Vinh =  1.125V
Vmeas =  0.750V
Cref =  0.0F
Rref =  1.000M
Vref =  0.0V
C_comp   4.200pF   3.800pF   7.500pF
[Temperature Range]   25.000   0.105k   -40.000
[Voltage Range]   1.500V   1.430V   1.580V
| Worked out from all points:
|   slope of the pulldown table from 0 to 0.225 V, typ, clamps not added: 40.7 ohm
|   slope of the pullup table from 0 to 0.225 V, typ, clamps not added: 38.9 ohm
|   GND clamp passes 1 mA (typ) near -0.44 V on its own axis
|   rising waveform, R_fixture 50.000, V_fixture 0.0: 20-80 % time 741ps typ, 1.18ns min, 438ps max; typ from 0 V to 0.582 V
|   rising waveform, R_fixture 50.000, V_fixture 1.500: 20-80 % time 365ps typ, 376ps min, 352ps max; typ from 0.933 V to 1.5 V
|   falling waveform, R_fixture 50.000, V_fixture 1.500: 20-80 % time 1.33ns typ, 2.24ns min, 756ps max; typ from 1.5 V to 0.933 V
|   falling waveform, R_fixture 50.000, V_fixture 0.0: 20-80 % time 387ps typ, 422ps min, 387ps max; typ from 0.582 V to 0 V
[Pulldown]
|Voltage   I(typ)   I(min)   I(max)
-1.5V     -19.1mA    -10.99mA   -29.96mA
-856mV    -19.1mA    -10.99mA   -29.96mA
-580mV    -16.64mA   -10.73mA   -25.56mA
-396mV    -12.04mA   -7.496mA   -19.19mA
156mV     4.064mA    2.312mA    6.984mA
524mV     9.661mA    5.388mA    16.51mA
938mV     11.37mA    6.303mA    19.16mA
1.812V    12.34mA    6.942mA    20.58mA
2.088V    14.22mA    9.341mA    21.9mA
2.226V    17.58mA    11.5mA     26.59mA
2.548V    27.18mA    18.02mA    43.16mA
3V        43.77mA    29.36mA    69.41mA
[Pullup]
|Voltage   I(typ)   I(min)   I(max)
-1.5V     77.88mA    50.86mA    132.1mA
-1.232V   63.14mA    43.18mA    106mA
-818mV    38.59mA    26.52mA    65.5mA
-634mV    27.65mA    19.25mA    45.6mA
-496mV    19.7mA     14.01mA    32.54mA
-312mV    11.25mA    7.838mA    18.9mA
-82mV     2.627mA    1.78mA     4.548mA
102mV     -2.891mA   -1.927mA   -5.109mA
286mV     -6.99mA    -4.605mA   -12.56mA
516mV     -10.15mA   -6.555mA   -18.77mA
792mV     -11.45mA   -7.225mA   -22.01mA
3V        -13.42mA   -8.343mA   -26.52mA
[GND_clamp]
|Voltage   I(typ)   I(min)   I(max)
-1.5V     -1.124A    -960.6mA   -1.411A
-1.097V   -411.6mA   -430.5mA   -392.9mA
-1.066V   -360.7mA   -392.1mA   -323mA
-1.035V   -311mA     -354.2mA   -256.7mA
-973mV    -216.8mA   -280.8mA   -144.3mA
-942mV    -173.5mA   -245.5mA   -105.7mA
-849mV    -71.06mA   -147.7mA   -64.61mA
-787mV    -39.17mA   -92.07mA   -53.7mA
-725mV    -26.41mA   -48.02mA   -41.6mA
-601mV    -11.16mA   -7.552mA   -18.74mA
-384mV    -258.6uA   -114.9uA   -396.2uA
1.5V      -41.68nA   0A         -8.283uA
[POWER_clamp]
|Voltage   I(typ)   I(min)   I(max)
-1.5V     553.8uA    455.7uA    723.9uA
-1.383V   462uA      386.8uA    600.3uA
-1.29V    390.6uA    333.2uA    514.8uA
-1.135V   279.1uA    247uA      410.2uA
-1.011V   206.7uA    182uA      336.5uA
-856mV    145uA      109.7uA    248.3uA
-732mV    104.8uA    66.29uA    183.2uA
-577mV    62.52uA    35.6uA     111.7uA
-422mV    33.03uA    19.13uA    58.98uA
-329mV    22.6uA     13.31uA    51.73uA
12mV      0A         0A         0A
1.5V      0A         0A         0A
[Ramp]
| variable   typ   min   max
dV/dt_r   0.349/0.742n   0.222/1.182n   0.599/0.435n
dV/dt_f   0.340/1.349n   0.194/2.206n   0.540/0.759n
R_load = 50.000
[Rising Waveform]
R_fixture= 50.000
V_fixture= 0.0
V_fixture_min= 0.0
V_fixture_max= 0.0
|time   V(typ)   V(min)   V(max)
0s        486.4uV    318.7uV    761.2uV
1.069ns   453.8uV    326uV      3.007mV
1.511ns   -11.09mV   418.3uV    650.1mV
1.706ns   -6.834mV   539.6uV    822.2mV
2.44ns    138.3mV    -3.726mV   976.2mV
3.056ns   445.4mV    -3.058mV   992.9mV
4.215ns   563.8mV    25.87mV    997.9mV
5.373ns   578.6mV    264.3mV    998.3mV
6.466ns   581.4mV    345.9mV    998.4mV
20ns      582.4mV    370.7mV    998.4mV
[Rising Waveform]
R_fixture= 50.000
V_fixture= 1.500
V_fixture_min= 1.430
V_fixture_max= 1.580
|time   V(typ)   V(min)   V(max)
0s        933mV      1.107V     680.4mV
695ps     933.1mV    1.107V     677.4mV
849ps     932.9mV    1.107V     1.072V
975ps     933mV      1.107V     1.271V
1.329ns   927.9mV    1.107V     1.533V
1.616ns   1.286V     1.107V     1.567V
2.345ns   1.467V     1.096V     1.578V
2.862ns   1.492V     1.353V     1.579V
3.712ns   1.499V     1.413V     1.58V
20ns      1.5V       1.43V      1.58V
[Falling Waveform]
R_fixture= 50.000
V_fixture= 1.500
V_fixture_min= 1.430
V_fixture_max= 1.580
|time   V(typ)   V(min)   V(max)
0s        1.5V       1.43V      1.58V
1.157ns   1.5V       1.43V      1.575V
1.848ns   1.515V     1.43V      1.02V
2.178ns   1.502V     1.431V     853.5mV
3.207ns   1.244V     1.446V     699.4mV
4.106ns   1.048V     1.43V      683.2mV
5.579ns   951.9mV    1.324V     680.5mV
7.23ns    935.4mV    1.178V     680.4mV
9.628ns   933.1mV    1.119V     680.4mV
20ns      933mV      1.107V     680.4mV
[Falling Waveform]
R_fixture= 50.000
V_fixture= 0.0
V_fixture_min= 0.0
V_fixture_max= 0.0
|time   V(typ)   V(min)   V(max)
0s        582.4mV    370.7mV    998.4mV
743ps     582.4mV    370.7mV    996mV
919ps     582.4mV    370.7mV    513.3mV
1.073ns   582.4mV    370.7mV    292.4mV
1.467ns   565.9mV    370.7mV    48.27mV
1.758ns   205.2mV    370.6mV    13.52mV
2.667ns   18.4mV     373.3mV    1.761mV
3.179ns   5.899mV    92.73mV    1.095mV
4.11ns    1.525mV    11.61mV    840.6uV
20ns      486.3uV    318.7uV    761.2uV
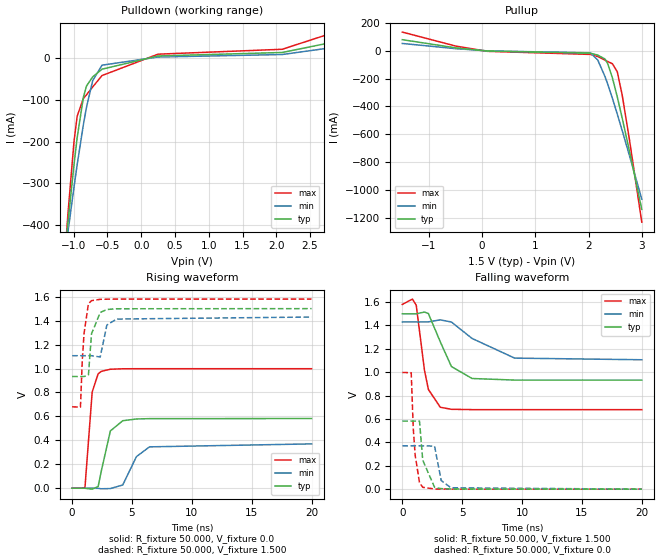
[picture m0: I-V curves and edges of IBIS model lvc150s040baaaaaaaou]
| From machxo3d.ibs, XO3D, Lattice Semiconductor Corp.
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|   Model lvc150s040baaaaaaaou
[Model] lvc150s040baaaaaaaou
Model_type Output
Polarity   Non-Inverting
Enable   Active-High
Vmeas =  0.750V
Cref =  0.0F
Rref =  1.000M
Vref =  0.0V
C_comp   4.200pF   3.800pF   7.500pF
[Temperature Range]   25.000   0.105k   -40.000
[Voltage Range]   1.500V   1.430V   1.580V
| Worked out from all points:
|   slope of the pulldown table from 0 to 0.225 V, typ, clamps not added: 40.7 ohm
|   slope of the pullup table from 0 to 0.225 V, typ, clamps not added: 38.8 ohm
|   rising waveform, R_fixture 50.000, V_fixture 0.0: 20-80 % time 741ps typ, 1.17ns min, 433ps max; typ from 0 V to 0.582 V
|   rising waveform, R_fixture 50.000, V_fixture 1.500: 20-80 % time 370ps typ, 380ps min, 347ps max; typ from 0.933 V to 1.5 V
|   falling waveform, R_fixture 50.000, V_fixture 1.500: 20-80 % time 1.34ns typ, 2.28ns min, 755ps max; typ from 1.5 V to 0.933 V
|   falling waveform, R_fixture 50.000, V_fixture 0.0: 20-80 % time 387ps typ, 418ps min, 372ps max; typ from 0.582 V to 0 V
[Pulldown]
|Voltage   I(typ)   I(min)   I(max)
-1.5V     -1.125A    -961.3mA   -1.413A
-1.132V   -473mA     -476mA     -480.5mA
-1.086V   -396.8mA   -418.5mA   -375.7mA
-994mV    -253.7mA   -307.5mA   -198.1mA
-948mV    -190mA     -254.9mA   -138.6mA
-856mV    -93.03mA   -158.7mA   -95.91mA
-810mV    -66.24mA   -117mA     -87.26mA
-718mV    -44.13mA   -53.14mA   -68.36mA
-580mV    -25.79mA   -16.16mA   -41.04mA
248mV     5.949mA    3.37mA     10.22mA
2.088V    14.29mA    9.39mA     21.99mA
3V        44.32mA    29.86mA    70.04mA
[Pullup]
|Voltage   I(typ)   I(min)   I(max)
-1.5V     78.43mA    51.31mA    132.8mA
-496mV    19.75mA    14.03mA    32.62mA
102mV     -2.897mA   -1.93mA    -5.12mA
2.034V    -18mA      -15.8mA    -27.11mA
2.172V    -31.96mA   -66.69mA   -42.39mA
2.31V     -60.54mA   -186.8mA   -67.94mA
2.356V    -89.72mA   -235.8mA   -77.06mA
2.448V    -194.7mA   -341.9mA   -93.99mA
2.54V     -332.1mA   -455mA     -152mA
2.632V    -483.4mA   -572.5mA   -318.5mA
2.77V     -722.8mA   -753.8mA   -641.9mA
3V        -1.137A    -1.064A    -1.229A
[Ramp]
| variable   typ   min   max
dV/dt_r   0.349/0.740n   0.222/1.189n   0.599/0.433n
dV/dt_f   0.340/1.345n   0.194/2.206n   0.540/0.758n
R_load = 50.000
[Rising Waveform]
R_fixture= 50.000
V_fixture= 0.0
V_fixture_min= 0.0
V_fixture_max= 0.0
|time   V(typ)   V(min)   V(max)
0s        486.4uV    318.7uV    761.2uV
1.07ns    474.7uV    324.9uV    3.429mV
1.676ns   -7.411mV   545uV      804.4mV
2.176ns   14.9mV     -719.3uV   956.3mV
2.438ns   144.2mV    -4mV       976.4mV
3.194ns   478.9mV    -2.508mV   994.1mV
4.227ns   564.2mV    27.57mV    997.8mV
5.372ns   578.6mV    264.5mV    998.3mV
6.46ns    581.5mV    345.9mV    998.4mV
20ns      582.4mV    370.7mV    998.4mV
[Rising Waveform]
R_fixture= 50.000
V_fixture= 1.500
V_fixture_min= 1.430
V_fixture_max= 1.580
|time   V(typ)   V(min)   V(max)
0s        933mV      1.107V     680.4mV
695ps     933.1mV    1.107V     677.4mV
849ps     933mV      1.107V     1.072V
1ns       933.1mV    1.107V     1.297V
1.363ns   947.2mV    1.107V     1.541V
1.619ns   1.289V     1.107V     1.567V
2.345ns   1.468V     1.096V     1.578V
2.902ns   1.493V     1.363V     1.579V
3.711ns   1.499V     1.413V     1.58V
20ns      1.5V       1.43V      1.58V
[Falling Waveform]
R_fixture= 50.000
V_fixture= 1.500
V_fixture_min= 1.430
V_fixture_max= 1.580
|time   V(typ)   V(min)   V(max)
0s        1.5V       1.43V      1.58V
843ps     1.5V       1.43V      1.626V
1.164ns   1.5V       1.43V      1.573V
1.848ns   1.515V     1.43V      1.019V
2.178ns   1.502V     1.431V     852.9mV
3.17ns    1.261V     1.448V     700.8mV
4.1ns     1.049V     1.43V      683.3mV
5.828ns   946.7mV    1.289V     680.6mV
9.381ns   933.2mV    1.121V     680.4mV
20ns      933mV      1.107V     680.3mV
[Falling Waveform]
R_fixture= 50.000
V_fixture= 0.0
V_fixture_min= 0.0
V_fixture_max= 0.0
|time   V(typ)   V(min)   V(max)
0s        582.4mV    370.7mV    998.4mV
743ps     582.4mV    370.7mV    996mV
919ps     582.4mV    370.7mV    513mV
1.072ns   582.4mV    370.7mV    291.8mV
1.435ns   582.7mV    370.7mV    56.45mV
1.705ns   248.6mV    370.7mV    16.12mV
2.693ns   16.19mV    368.7mV    1.639mV
3.25ns    4.787mV    73.83mV    1.029mV
4.066ns   1.597mV    11.98mV    814.1uV
20ns      486.4uV    318.7uV    761.2uV
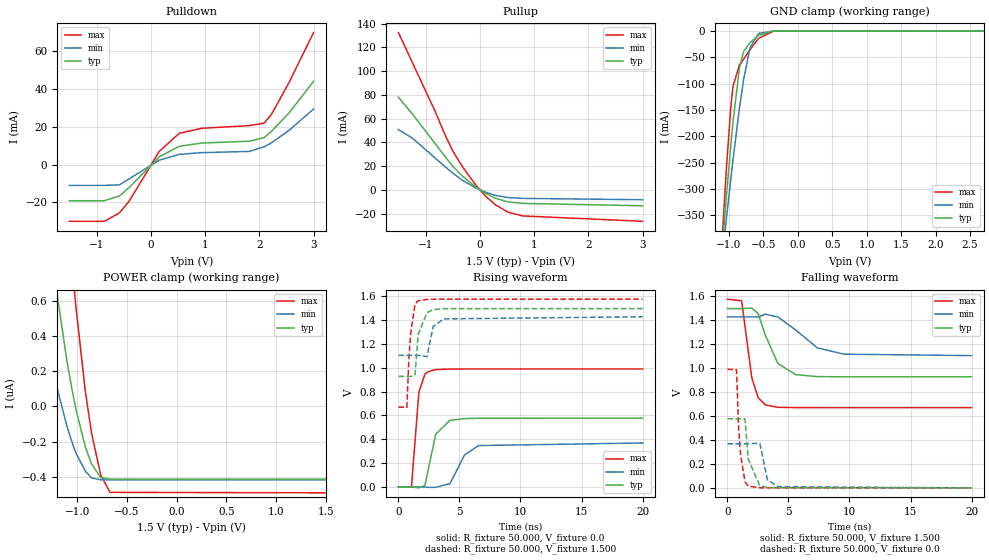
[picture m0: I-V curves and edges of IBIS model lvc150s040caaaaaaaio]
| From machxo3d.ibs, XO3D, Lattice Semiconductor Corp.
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|   Model lvc150s040caaaaaaaio
[Model] lvc150s040caaaaaaaio
Model_type I/O
Polarity   Non-Inverting
Enable   Active-Low
Vinl =  0.375V
Vinh =  1.125V
Vmeas =  0.750V
Cref =  0.0F
Rref =  1.000M
Vref =  0.0V
C_comp   4.200pF   3.800pF   7.500pF
[Temperature Range]   25.000   0.105k   -40.000
[Voltage Range]   1.500V   1.430V   1.580V
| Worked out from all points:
|   slope of the pulldown table from 0 to 0.225 V, typ, clamps not added: 40.7 ohm
|   slope of the pullup table from 0 to 0.225 V, typ, clamps not added: 38.9 ohm
|   GND clamp passes 1 mA (typ) near -0.43 V on its own axis
|   rising waveform, R_fixture 50.000, V_fixture 0.0: 20-80 % time 743ps typ, 1.18ns min, 437ps max; typ from 0 V to 0.577 V
|   rising waveform, R_fixture 50.000, V_fixture 1.500: 20-80 % time 373ps typ, 381ps min, 360ps max; typ from 0.928 V to 1.5 V
|   falling waveform, R_fixture 50.000, V_fixture 1.500: 20-80 % time 1.34ns typ, 2.22ns min, 761ps max; typ from 1.5 V to 0.928 V
|   falling waveform, R_fixture 50.000, V_fixture 0.0: 20-80 % time 384ps typ, 421ps min, 358ps max; typ from 0.577 V to 0 V
[Pulldown]
|Voltage   I(typ)   I(min)   I(max)
-1.5V     -19.1mA    -10.99mA   -29.96mA
-856mV    -19.1mA    -10.99mA   -29.96mA
-580mV    -16.64mA   -10.73mA   -25.56mA
-396mV    -12.04mA   -7.496mA   -19.19mA
156mV     4.064mA    2.312mA    6.984mA
524mV     9.661mA    5.388mA    16.51mA
938mV     11.37mA    6.303mA    19.16mA
1.812V    12.33mA    6.941mA    20.58mA
2.088V    14.23mA    9.35mA     21.86mA
2.226V    17.61mA    11.53mA    26.61mA
2.548V    27.26mA    18.07mA    43.3mA
3V        43.98mA    29.3mA     69.72mA
[Pullup]
|Voltage   I(typ)   I(min)   I(max)
-1.5V     78.08mA    50.79mA    132.5mA
-1.232V   63.29mA    43.22mA    106.2mA
-818mV    38.63mA    26.55mA    65.6mA
-634mV    27.67mA    19.25mA    45.62mA
-496mV    19.69mA    14.01mA    32.5mA
-312mV    11.24mA    7.837mA    18.9mA
-82mV     2.627mA    1.78mA     4.548mA
102mV     -2.891mA   -1.927mA   -5.109mA
286mV     -6.99mA    -4.605mA   -12.56mA
516mV     -10.15mA   -6.555mA   -18.77mA
792mV     -11.45mA   -7.225mA   -22.01mA
3V        -13.42mA   -8.343mA   -26.52mA
[GND_clamp]
|Voltage   I(typ)   I(min)   I(max)
-1.5V     -1.124A    -960.6mA   -1.411A
-1.097V   -411.6mA   -430.5mA   -393mA
-1.066V   -360.7mA   -392.1mA   -323mA
-1.035V   -311mA     -354.2mA   -256.8mA
-973mV    -216.9mA   -280.8mA   -144.3mA
-942mV    -173.5mA   -245.5mA   -105.7mA
-849mV    -71.09mA   -147.7mA   -64.66mA
-787mV    -39.21mA   -92.09mA   -53.75mA
-694mV    -22.05mA   -31.84mA   -35.55mA
-570mV    -8.285mA   -4.678mA   -14.06mA
-353mV    -178.3uA   -91.12uA   -279.1uA
3V        108.1uA    41.24uA    254.4uA
[POWER_clamp]
|Voltage   I(typ)   I(min)   I(max)
-1.5V     2.264uA    1.09uA     5.325uA
-1.383V   1.543uA    646.9nA    3.832uA
-1.29V    1.045uA    348.8nA    2.802uA
-1.197V   619.1nA    96.02nA    1.914uA
-1.104V   264.3nA    -108.5nA   1.168uA
-1.042V   67.87nA    -217.5nA   747.1nA
-1.011V   -18.19nA   -263.5nA   559.8nA
-918mV    -227nA     -366.2nA   89.61nA
-856mV    -324nA     -403.7nA   -147.4nA
-763mV    -403.1nA   -415.8nA   -387.4nA
-670mV    -411.5nA   -415.8nA   -486.7nA
1.5V      -411.5nA   -415.8nA   -489.2nA
[Ramp]
| variable   typ   min   max
dV/dt_r   0.346/0.741n   0.221/1.189n   0.594/0.437n
dV/dt_f   0.342/1.354n   0.194/2.220n   0.544/0.753n
R_load = 50.000
[Rising Waveform]
R_fixture= 50.000
V_fixture= 0.0
V_fixture_min= 0.0
V_fixture_max= 0.0
|time   V(typ)   V(min)   V(max)
0s        4.549nV    50.98nV    2.322nV
1.07ns    -34.28uV   10.15uV    1.547mV
1.678ns   -8.183mV   213uV      796.1mV
2.17ns    12.25mV    -1.044mV   946.8mV
2.443ns   145.6mV    -4.326mV   968.3mV
3.064ns   444.1mV    -3.566mV   985.1mV
4.229ns   559.3mV    27.27mV    990.1mV
5.412ns   573.8mV    268.3mV    990.5mV
6.574ns   576.5mV    347.3mV    990.6mV
20ns      577.2mV    368.8mV    990.6mV
[Rising Waveform]
R_fixture= 50.000
V_fixture= 1.500
V_fixture_min= 1.430
V_fixture_max= 1.580
|time   V(typ)   V(min)   V(max)
0s        927.7mV    1.105V     670.5mV
695ps     927.7mV    1.105V     667.5mV
851ps     927.5mV    1.105V     1.064V
1.002ns   927.7mV    1.105V     1.285V
1.365ns   943.4mV    1.105V     1.536V
1.616ns   1.281V     1.105V     1.563V
2.347ns   1.464V     1.094V     1.575V
2.842ns   1.489V     1.346V     1.576V
3.707ns   1.497V     1.411V     1.577V
20ns      1.498V     1.429V     1.577V
[Falling Waveform]
R_fixture= 50.000
V_fixture= 1.500
V_fixture_min= 1.430
V_fixture_max= 1.580
|time   V(typ)   V(min)   V(max)
0s        1.498V     1.429V     1.577V
1.163ns   1.498V     1.429V     1.563V
1.999ns   1.502V     1.429V     919.3mV
2.514ns   1.457V     1.428V     753.1mV
3.117ns   1.273V     1.451V     692.8mV
4.133ns   1.039V     1.428V     673.2mV
5.595ns   946.2mV    1.319V     670.7mV
7.357ns   929.6mV    1.17V      670.5mV
9.554ns   927.8mV    1.117V     670.5mV
20ns      927.7mV    1.105V     670.5mV
[Falling Waveform]
R_fixture= 50.000
V_fixture= 0.0
V_fixture_min= 0.0
V_fixture_max= 0.0
|time   V(typ)   V(min)   V(max)
0s        577.2mV    368.8mV    990.6mV
743ps     577.3mV    368.8mV    988.1mV
919ps     577.3mV    368.8mV    502.2mV
1.077ns   577.3mV    368.8mV    277.3mV
1.437ns   576.9mV    368.8mV    52.02mV
1.709ns   240.3mV    368.8mV    14.32mV
2.654ns   17.51mV    372.7mV    1.083mV
3.282ns   3.86mV     66.02mV    264.9uV
4.18ns    899.2uV    9.792mV    47.82uV
20ns      7.127nV    114.5nV    -10.93nV
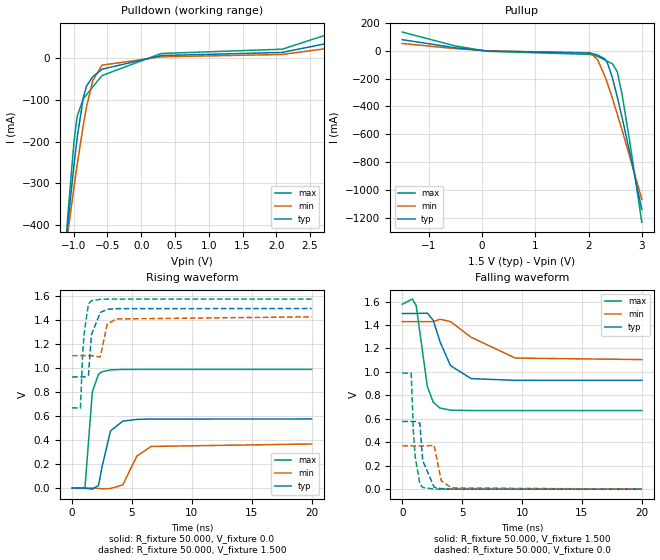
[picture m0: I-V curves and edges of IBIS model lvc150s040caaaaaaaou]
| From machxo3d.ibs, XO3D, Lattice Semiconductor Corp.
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|   Model lvc150s040caaaaaaaou
[Model] lvc150s040caaaaaaaou
Model_type Output
Polarity   Non-Inverting
Enable   Active-High
Vmeas =  0.750V
Cref =  0.0F
Rref =  1.000M
Vref =  0.0V
C_comp   4.200pF   3.800pF   7.500pF
[Temperature Range]   25.000   0.105k   -40.000
[Voltage Range]   1.500V   1.430V   1.580V
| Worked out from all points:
|   slope of the pulldown table from 0 to 0.225 V, typ, clamps not added: 40.4 ohm
|   slope of the pullup table from 0 to 0.225 V, typ, clamps not added: 38.9 ohm
|   rising waveform, R_fixture 50.000, V_fixture 0.0: 20-80 % time 745ps typ, 1.18ns min, 438ps max; typ from 0 V to 0.577 V
|   rising waveform, R_fixture 50.000, V_fixture 1.500: 20-80 % time 374ps typ, 378ps min, 356ps max; typ from 0.928 V to 1.5 V
|   falling waveform, R_fixture 50.000, V_fixture 1.500: 20-80 % time 1.36ns typ, 2.24ns min, 753ps max; typ from 1.5 V to 0.928 V
|   falling waveform, R_fixture 50.000, V_fixture 0.0: 20-80 % time 381ps typ, 414ps min, 362ps max; typ from 0.577 V to 0 V
[Pulldown]
|Voltage   I(typ)   I(min)   I(max)
-1.5V     -1.125A    -961.3mA   -1.413A
-1.132V   -473mA     -476mA     -480.5mA
-1.086V   -396.8mA   -418.5mA   -375.7mA
-994mV    -253.7mA   -307.5mA   -198.1mA
-948mV    -190.1mA   -254.9mA   -138.7mA
-856mV    -93.06mA   -158.7mA   -95.96mA
-810mV    -66.28mA   -117mA     -87.3mA
-718mV    -44.17mA   -53.17mA   -68.41mA
-580mV    -25.84mA   -16.2mA    -41.11mA
294mV     6.851mA    3.862mA    11.81mA
2.088V    14.33mA    9.389mA    22.11mA
3V        44.09mA    29.34mA    69.98mA
[Pullup]
|Voltage   I(typ)   I(min)   I(max)
-1.5V     78.19mA    50.83mA    132.7mA
-496mV    19.8mA     14.04mA    32.75mA
102mV     -2.791mA   -1.89mA    -4.87mA
2.034V    -18.04mA   -15.83mA   -27.19mA
2.172V    -31.99mA   -66.7mA    -42.44mA
2.31V     -60.56mA   -186.8mA   -67.97mA
2.356V    -89.75mA   -235.8mA   -77.09mA
2.448V    -194.7mA   -341.9mA   -94.02mA
2.54V     -332.1mA   -455mA     -152mA
2.632V    -483.5mA   -572.5mA   -318.5mA
2.77V     -722.8mA   -753.8mA   -642mA
3V        -1.137A    -1.064A    -1.229A
[Ramp]
| variable   typ   min   max
dV/dt_r   0.346/0.739n   0.221/1.188n   0.594/0.435n
dV/dt_f   0.342/1.350n   0.194/2.216n   0.544/0.757n
R_load = 50.000
[Rising Waveform]
R_fixture= 50.000
V_fixture= 0.0
V_fixture_min= 0.0
V_fixture_max= 0.0
|time   V(typ)   V(min)   V(max)
0s        4.508nV    51.14nV    2.279nV
1.07ns    -23.35uV   6.076uV    1.527mV
1.688ns   -8.073mV   227.5uV    804.1mV
2.21ns    24.12mV    -972.7uV   951.6mV
2.485ns   171.7mV    -5.17mV    970.6mV
3.202ns   476.7mV    -2.969mV   986.3mV
4.229ns   559.4mV    27.45mV    990.1mV
5.41ns    573.8mV    268.4mV    990.5mV
6.599ns   576.5mV    348.2mV    990.6mV
20ns      577.2mV    368.8mV    990.6mV
[Rising Waveform]
R_fixture= 50.000
V_fixture= 1.500
V_fixture_min= 1.430
V_fixture_max= 1.580
|time   V(typ)   V(min)   V(max)
0s        927.7mV    1.105V     670.5mV
695ps     927.7mV    1.105V     667.5mV
889ps     927.5mV    1.105V     1.141V
1.012ns   927.7mV    1.105V     1.296V
1.363ns   941.8mV    1.105V     1.536V
1.613ns   1.279V     1.105V     1.563V
2.353ns   1.465V     1.094V     1.575V
2.922ns   1.491V     1.365V     1.576V
3.669ns   1.497V     1.411V     1.577V
20ns      1.498V     1.429V     1.577V
[Falling Waveform]
R_fixture= 50.000
V_fixture= 1.500
V_fixture_min= 1.430
V_fixture_max= 1.580
|time   V(typ)   V(min)   V(max)
0s        1.498V     1.429V     1.577V
840ps     1.498V     1.429V     1.621V
1.158ns   1.498V     1.429V     1.565V
2.09ns    1.501V     1.429V     875.7mV
2.583ns   1.44V      1.429V     741.2mV
3.149ns   1.257V     1.449V     691.3mV
4.021ns   1.054V     1.429V     673.7mV
5.75ns    942.6mV    1.295V     670.6mV
9.439ns   927.9mV    1.118V     670.5mV
20ns      927.7mV    1.105V     670.5mV
[Falling Waveform]
R_fixture= 50.000
V_fixture= 0.0
V_fixture_min= 0.0
V_fixture_max= 0.0
|time   V(typ)   V(min)   V(max)
0s        577.2mV    368.8mV    990.6mV
743ps     577.3mV    368.8mV    988.1mV
921ps     577.3mV    368.8mV    497.6mV
1.079ns   577.4mV    368.8mV    273.6mV
1.465ns   562.3mV    368.8mV    43.98mV
1.706ns   242.7mV    368.8mV    14.4mV
2.659ns   16.9mV     372.3mV    1.041mV
3.25ns    4.03mV     72.37mV    245.1uV
4.106ns   988.4uV    10.55mV    44.67uV
20ns      11.54nV    115.6nV    10.71nV
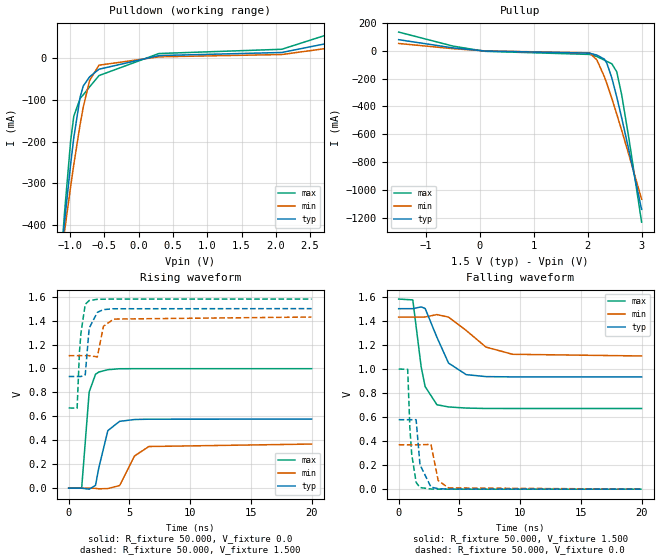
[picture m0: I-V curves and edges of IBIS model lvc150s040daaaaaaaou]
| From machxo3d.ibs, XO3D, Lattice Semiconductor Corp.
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|   Model lvc150s040daaaaaaaou
[Model] lvc150s040daaaaaaaou
Model_type Output
Polarity   Non-Inverting
Enable   Active-High
Vmeas =  0.750V
Cref =  0.0F
Rref =  1.000M
Vref =  0.0V
C_comp   4.200pF   3.800pF   7.500pF
[Temperature Range]   25.000   0.105k   -40.000
[Voltage Range]   1.500V   1.430V   1.580V
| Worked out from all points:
|   slope of the pulldown table from 0 to 0.225 V, typ, clamps not added: 40.4 ohm
|   slope of the pullup table from 0 to 0.225 V, typ, clamps not added: 38.8 ohm
|   rising waveform, R_fixture 50.000, V_fixture 0.0: 20-80 % time 747ps typ, 1.18ns min, 445ps max; typ from 0 V to 0.577 V
|   rising waveform, R_fixture 50.000, V_fixture 1.500: 20-80 % time 366ps typ, 377ps min, 356ps max; typ from 0.933 V to 1.5 V
|   falling waveform, R_fixture 50.000, V_fixture 1.500: 20-80 % time 1.34ns typ, 2.24ns min, 773ps max; typ from 1.5 V to 0.933 V
|   falling waveform, R_fixture 50.000, V_fixture 0.0: 20-80 % time 378ps typ, 414ps min, 372ps max; typ from 0.577 V to 0 V
[Pulldown]
|Voltage   I(typ)   I(min)   I(max)
-1.5V     -1.125A    -961.3mA   -1.413A
-1.132V   -473mA     -476mA     -480.5mA
-1.086V   -396.8mA   -418.5mA   -375.7mA
-994mV    -253.7mA   -307.5mA   -198.1mA
-948mV    -190.1mA   -254.9mA   -138.7mA
-856mV    -93.06mA   -158.7mA   -95.96mA
-810mV    -66.28mA   -117mA     -87.3mA
-718mV    -44.17mA   -53.17mA   -68.41mA
-580mV    -25.84mA   -16.2mA    -41.11mA
294mV     6.851mA    3.862mA    11.81mA
2.088V    14.29mA    9.39mA     21.99mA
3V        44.32mA    29.86mA    70.04mA
[Pullup]
|Voltage   I(typ)   I(min)   I(max)
-1.5V     78.43mA    51.31mA    132.8mA
-496mV    19.75mA    14.03mA    32.62mA
102mV     -2.897mA   -1.93mA    -5.12mA
2.034V    -18.04mA   -15.83mA   -27.19mA
2.172V    -31.99mA   -66.7mA    -42.44mA
2.31V     -60.56mA   -186.8mA   -67.97mA
2.356V    -89.75mA   -235.8mA   -77.09mA
2.448V    -194.7mA   -341.9mA   -94.02mA
2.54V     -332.1mA   -455mA     -152mA
2.632V    -483.5mA   -572.5mA   -318.5mA
2.77V     -722.8mA   -753.8mA   -642mA
3V        -1.137A    -1.064A    -1.229A
[Ramp]
| variable   typ   min   max
dV/dt_r   0.346/0.739n   0.221/1.188n   0.599/0.444n
dV/dt_f   0.340/1.345n   0.194/2.206n   0.546/0.778n
R_load = 50.000
[Rising Waveform]
R_fixture= 50.000
V_fixture= 0.0
V_fixture_min= 0.0
V_fixture_max= 0.0
|time   V(typ)   V(min)   V(max)
0s        4.508nV    51.14nV    2.279nV
1.07ns    -23.35uV   6.019uV    1.527mV
1.688ns   -8.073mV   227.5uV    804.1mV
2.21ns    24.12mV    -972.7uV   951.6mV
2.485ns   171.7mV    -5.17mV    970.6mV
3.224ns   481mV      -2.971mV   989.9mV
4.195ns   558.5mV    22.38mV    997.9mV
5.41ns    573.8mV    268.4mV    998.3mV
6.599ns   576.5mV    348.2mV    998.4mV
20ns      577.2mV    368.8mV    998.4mV
[Rising Waveform]
R_fixture= 50.000
V_fixture= 1.500
V_fixture_min= 1.430
V_fixture_max= 1.580
|time   V(typ)   V(min)   V(max)
0s        933mV      1.107V     670.5mV
695ps     933.1mV    1.107V     667.5mV
889ps     932.9mV    1.107V     1.141V
1.012ns   933.1mV    1.107V     1.296V
1.363ns   947.2mV    1.107V     1.536V
1.69ns    1.338V     1.107V     1.568V
2.36ns    1.469V     1.097V     1.578V
2.862ns   1.492V     1.353V     1.579V
3.711ns   1.499V     1.413V     1.58V
20ns      1.5V       1.43V      1.58V
[Falling Waveform]
R_fixture= 50.000
V_fixture= 1.500
V_fixture_min= 1.430
V_fixture_max= 1.580
|time   V(typ)   V(min)   V(max)
0s        1.5V       1.43V      1.58V
1.164ns   1.5V       1.43V      1.573V
1.848ns   1.515V     1.43V      1.019V
2.178ns   1.502V     1.431V     852.9mV
3.147ns   1.263V     1.451V     701.8mV
4.105ns   1.048V     1.43V      683.3mV
5.559ns   952mV      1.319V     674.1mV
7.184ns   935.5mV    1.181V     670.6mV
9.381ns   933.2mV    1.121V     670.5mV
20ns      933mV      1.107V     670.5mV
[Falling Waveform]
R_fixture= 50.000
V_fixture= 0.0
V_fixture_min= 0.0
V_fixture_max= 0.0
|time   V(typ)   V(min)   V(max)
0s        577.2mV    368.8mV    998.4mV
743ps     577.3mV    368.8mV    996mV
919ps     577.3mV    368.8mV    513mV
1.072ns   577.3mV    368.8mV    291.8mV
1.435ns   577.6mV    368.8mV    56.45mV
1.754ns   202.9mV    368.8mV    13.57mV
2.659ns   16.9mV     372.3mV    1.096mV
3.25ns    4.03mV     72.37mV    270.6uV
4.106ns   988.4uV    10.55mV    53.51uV
20ns      11.54nV    115.6nV    5.128nV
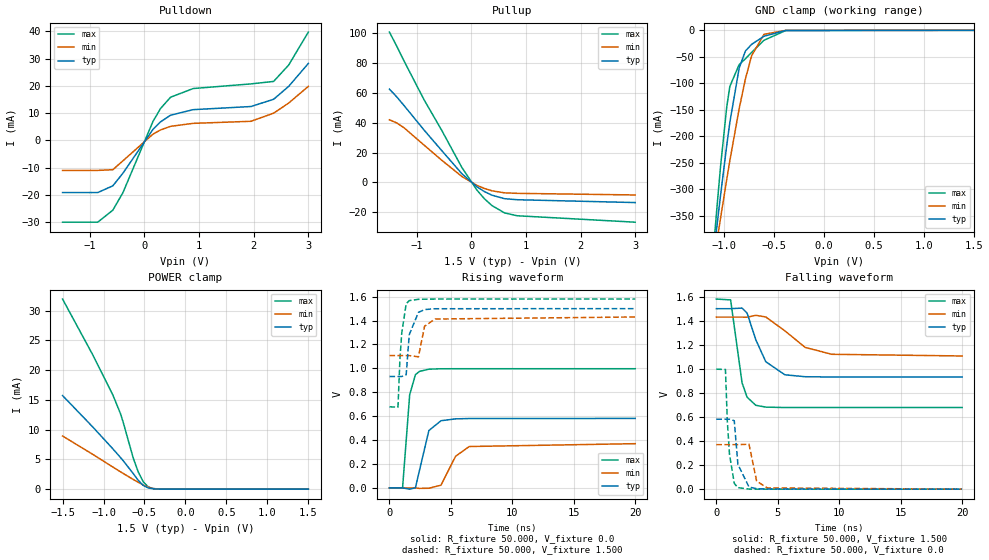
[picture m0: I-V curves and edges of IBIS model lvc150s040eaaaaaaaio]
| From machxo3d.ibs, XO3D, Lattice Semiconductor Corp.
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|   Model lvc150s040eaaaaaaaio
[Model] lvc150s040eaaaaaaaio
Model_type I/O
Polarity   Non-Inverting
Enable   Active-Low
Vinl =  0.375V
Vinh =  1.125V
Vmeas =  0.750V
Cref =  0.0F
Rref =  1.000M
Vref =  0.0V
C_comp   4.200pF   3.800pF   7.500pF
[Temperature Range]   25.000   0.105k   -40.000
[Voltage Range]   1.500V   1.430V   1.580V
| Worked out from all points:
|   slope of the pulldown table from 0 to 0.225 V, typ, clamps not added: 40.7 ohm
|   slope of the pullup table from 0 to 0.225 V, typ, clamps not added: 38.9 ohm
|   GND clamp passes 1 mA (typ) near -0.44 V on its own axis
|   POWER clamp passes 1 mA (typ) near -0.55 V on its own axis
|   rising waveform, R_fixture 50.000, V_fixture 0.0: 20-80 % time 750ps typ, 1.17ns min, 437ps max; typ from 0 V to 0.581 V
|   rising waveform, R_fixture 50.000, V_fixture 1.500: 20-80 % time 370ps typ, 379ps min, 348ps max; typ from 0.932 V to 1.5 V
|   falling waveform, R_fixture 50.000, V_fixture 1.500: 20-80 % time 1.36ns typ, 2.26ns min, 757ps max; typ from 1.5 V to 0.932 V
|   falling waveform, R_fixture 50.000, V_fixture 0.0: 20-80 % time 386ps typ, 423ps min, 367ps max; typ from 0.581 V to 0 V
[Pulldown]
|Voltage   I(typ)   I(min)   I(max)
-1.5V     -19.1mA    -10.99mA   -29.96mA
-856mV    -19.1mA    -10.99mA   -29.96mA
-580mV    -16.64mA   -10.73mA   -25.56mA
-396mV    -12.04mA   -7.496mA   -19.19mA
156mV     4.064mA    2.312mA    6.984mA
294mV     6.796mA    3.838mA    11.69mA
478mV     9.247mA    5.168mA    15.84mA
892mV     11.27mA    6.25mA     19.01mA
1.95V     12.42mA    7.008mA    20.71mA
2.364V    15.07mA    9.98mA     21.61mA
2.64V     19.8mA     13.69mA    27.61mA
3V        28.2mA     19.8mA     39.69mA
[Pullup]
|Voltage   I(typ)   I(min)   I(max)
-1.5V     62.29mA    41.83mA    100.4mA
-1.37V    57.3mA     39.82mA    91.24mA
-1.232V   51.32mA    36.48mA    81.04mA
-864mV    34.92mA    24.88mA    55.09mA
-542mV    21.27mA    14.84mA    34.76mA
-174mV    5.857mA    4.015mA    10.01mA
102mV     -2.891mA   -1.927mA   -5.109mA
240mV     -6.098mA   -4.031mA   -10.91mA
378mV     -8.511mA   -5.568mA   -15.45mA
608mV     -10.83mA   -6.929mA   -20.32mA
838mV     -11.52mA   -7.262mA   -22.22mA
3V        -13.42mA   -8.343mA   -26.52mA
[GND_clamp]
|Voltage   I(typ)   I(min)   I(max)
-1.5V     -1.124A    -960.6mA   -1.411A
-1.097V   -411.6mA   -430.5mA   -392.9mA
-1.066V   -360.7mA   -392.1mA   -323mA
-1.035V   -311mA     -354.2mA   -256.7mA
-973mV    -216.8mA   -280.8mA   -144.2mA
-942mV    -173.4mA   -245.5mA   -105.6mA
-849mV    -71.05mA   -147.7mA   -64.59mA
-787mV    -39.16mA   -92.07mA   -53.68mA
-725mV    -26.4mA    -48.02mA   -41.58mA
-601mV    -11.15mA   -7.544mA   -18.72mA
-384mV    -236.4uA   -103.3uA   -351.1uA
1.5V      0A         0A         0A
[POWER_clamp]
|Voltage   I(typ)   I(min)   I(max)
-1.5V     15.72mA    8.929mA    31.93mA
-1.135V   10.5mA     5.879mA    22.65mA
-887mV    6.787mA    3.722mA    15.85mA
-794mV    5.333mA    2.928mA    12.72mA
-763mV    4.831mA    2.666mA    11.38mA
-639mV    2.654mA    1.642mA    5.303mA
-577mV    1.493mA    1.154mA    2.909mA
-515mV    627.3uA    700.9uA    1.235mA
-453mV    200.7uA    325.5uA    363.9uA
-391mV    56.19uA    99.29uA    82.51uA
-298mV    7.73uA     11.12uA    7.668uA
1.5V      0A         0A         4.131nA
[Ramp]
| variable   typ   min   max
dV/dt_r   0.349/0.744n   0.222/1.182n   0.598/0.436n
dV/dt_f   0.341/1.345n   0.194/2.246n   0.541/0.758n
R_load = 50.000
[Rising Waveform]
R_fixture= 50.000
V_fixture= 0.0
V_fixture_min= 0.0
V_fixture_max= 0.0
|time   V(typ)   V(min)   V(max)
0s        4.722nV    51.53nV    2.531nV
1.07ns    -41.84uV   6.854uV    1.343mV
1.646ns   -10.61mV   221.9uV    779mV
2.115ns   960.7uV    -717.4uV   946.9mV
2.444ns   146.5mV    -4.046mV   975.1mV
3.208ns   479.9mV    -2.993mV   993.2mV
4.195ns   562.1mV    22.36mV    996.7mV
5.381ns   577.6mV    264.7mV    997.1mV
6.494ns   580.4mV    346.2mV    997.1mV
20ns      581.2mV    370.1mV    997.2mV
[Rising Waveform]
R_fixture= 50.000
V_fixture= 1.500
V_fixture_min= 1.430
V_fixture_max= 1.580
|time   V(typ)   V(min)   V(max)
0s        932.1mV    1.107V     678.4mV
695ps     932.1mV    1.107V     675.4mV
849ps     932mV      1.107V     1.07V
1.003ns   932.1mV    1.107V     1.297V
1.363ns   946.2mV    1.107V     1.541V
1.61ns    1.281V     1.107V     1.567V
2.36ns    1.469V     1.097V     1.578V
2.86ns    1.492V     1.353V     1.579V
3.713ns   1.499V     1.413V     1.58V
20ns      1.5V       1.43V      1.58V
[Falling Waveform]
R_fixture= 50.000
V_fixture= 1.500
V_fixture_min= 1.430
V_fixture_max= 1.580
|time   V(typ)   V(min)   V(max)
0s        1.5V       1.43V      1.58V
1.163ns   1.5V       1.43V      1.573V
2.096ns   1.505V     1.43V      884mV
2.502ns   1.464V     1.429V     764.9mV
3.214ns   1.242V     1.445V     697.1mV
4.026ns   1.059V     1.431V     681.9mV
5.579ns   950.7mV    1.316V     678.5mV
7.235ns   934.5mV    1.178V     678.4mV
9.401ns   932.3mV    1.121V     678.4mV
20ns      932.1mV    1.107V     678.4mV
[Falling Waveform]
R_fixture= 50.000
V_fixture= 0.0
V_fixture_min= 0.0
V_fixture_max= 0.0
|time   V(typ)   V(min)   V(max)
0s        581.2mV    370.1mV    997.2mV
743ps     581.3mV    370.1mV    994.8mV
895ps     581.3mV    370.1mV    565.5mV
1.072ns   581.3mV    370.1mV    290.8mV
1.461ns   569.1mV    370.1mV    48.31mV
1.754ns   206.9mV    370.1mV    12.66mV
2.659ns   17.78mV    373.6mV    978.4uV
3.282ns   3.95mV     66.85mV    218.3uV
4.148ns   939.8uV    10.44mV    75.33uV
20ns      10.8nV     117.3nV    1.733nV
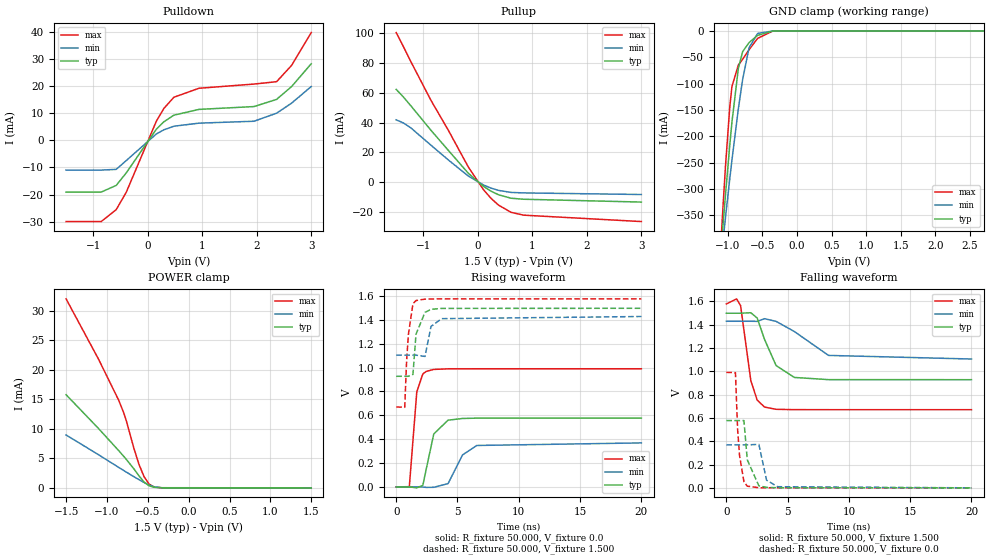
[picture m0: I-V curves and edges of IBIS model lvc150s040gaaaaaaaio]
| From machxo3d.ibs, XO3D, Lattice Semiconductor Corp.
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|   Model lvc150s040gaaaaaaaio
[Model] lvc150s040gaaaaaaaio
Model_type I/O
Polarity   Non-Inverting
Enable   Active-Low
Vinl =  0.375V
Vinh =  1.125V
Vmeas =  0.750V
Cref =  0.0F
Rref =  1.000M
Vref =  0.0V
C_comp   4.200pF   3.800pF   7.500pF
[Temperature Range]   25.000   0.105k   -40.000
[Voltage Range]   1.500V   1.430V   1.580V
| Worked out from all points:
|   slope of the pulldown table from 0 to 0.225 V, typ, clamps not added: 40.7 ohm
|   slope of the pullup table from 0 to 0.225 V, typ, clamps not added: 38.9 ohm
|   GND clamp passes 1 mA (typ) near -0.43 V on its own axis
|   POWER clamp passes 1 mA (typ) near -0.55 V on its own axis
|   rising waveform, R_fixture 50.000, V_fixture 0.0: 20-80 % time 743ps typ, 1.18ns min, 437ps max; typ from 0 V to 0.577 V
|   rising waveform, R_fixture 50.000, V_fixture 1.500: 20-80 % time 373ps typ, 381ps min, 360ps max; typ from 0.928 V to 1.5 V
|   falling waveform, R_fixture 50.000, V_fixture 1.500: 20-80 % time 1.34ns typ, 2.22ns min, 761ps max; typ from 1.5 V to 0.928 V
|   falling waveform, R_fixture 50.000, V_fixture 0.0: 20-80 % time 384ps typ, 421ps min, 358ps max; typ from 0.577 V to 0 V
[Pulldown]
|Voltage   I(typ)   I(min)   I(max)
-1.5V     -19.1mA    -10.99mA   -29.96mA
-856mV    -19.1mA    -10.99mA   -29.96mA
-580mV    -16.64mA   -10.73mA   -25.56mA
-396mV    -12.04mA   -7.496mA   -19.19mA
156mV     4.064mA    2.312mA    6.984mA
294mV     6.796mA    3.838mA    11.69mA
478mV     9.247mA    5.168mA    15.84mA
938mV     11.37mA    6.303mA    19.16mA
1.95V     12.42mA    7.008mA    20.71mA
2.364V    15.06mA    9.98mA     21.58mA
2.64V     19.8mA     13.69mA    27.6mA
3V        28.19mA    19.8mA     39.68mA
[Pullup]
|Voltage   I(typ)   I(min)   I(max)
-1.5V     62.3mA     41.83mA    100.5mA
-1.37V    57.3mA     39.82mA    91.24mA
-1.232V   51.32mA    36.48mA    81.03mA
-864mV    34.92mA    24.88mA    55.08mA
-542mV    21.27mA    14.84mA    34.76mA
-174mV    5.857mA    4.015mA    10.01mA
102mV     -2.891mA   -1.927mA   -5.109mA
240mV     -6.098mA   -4.031mA   -10.91mA
378mV     -8.511mA   -5.568mA   -15.45mA
608mV     -10.83mA   -6.929mA   -20.32mA
838mV     -11.52mA   -7.262mA   -22.22mA
3V        -13.42mA   -8.343mA   -26.52mA
[GND_clamp]
|Voltage   I(typ)   I(min)   I(max)
-1.5V     -1.124A    -960.6mA   -1.411A
-1.097V   -411.6mA   -430.5mA   -393mA
-1.066V   -360.7mA   -392.1mA   -323mA
-1.035V   -311mA     -354.2mA   -256.8mA
-973mV    -216.9mA   -280.8mA   -144.3mA
-942mV    -173.5mA   -245.5mA   -105.7mA
-849mV    -71.09mA   -147.7mA   -64.66mA
-787mV    -39.21mA   -92.09mA   -53.75mA
-694mV    -22.05mA   -31.84mA   -35.55mA
-570mV    -8.285mA   -4.678mA   -14.06mA
-353mV    -178.3uA   -91.12uA   -279.1uA
3V        108.1uA    41.24uA    254.4uA
[POWER_clamp]
|Voltage   I(typ)   I(min)   I(max)
-1.5V     15.78mA    8.958mA    32.02mA
-1.104V   10.07mA    5.622mA    21.83mA
-856mV    6.305mA    3.46mA     14.84mA
-794mV    5.324mA    2.93mA     12.69mA
-763mV    4.82mA     2.667mA    11.36mA
-670mV    3.216mA    1.891mA    6.697mA
-608mV    2.042mA    1.391mA    3.973mA
-546mV    979.4uA    916.1uA    1.9mA
-484mV    340.1uA    494.4uA    627.5uA
-422mV    90.48uA    185.7uA    125.7uA
-329mV    10.53uA    21.57uA    6.907uA
1.5V      0A         0A         -3.95nA
[Ramp]
| variable   typ   min   max
dV/dt_r   0.346/0.741n   0.221/1.189n   0.594/0.437n
dV/dt_f   0.342/1.354n   0.194/2.220n   0.544/0.753n
R_load = 50.000
[Rising Waveform]
R_fixture= 50.000
V_fixture= 0.0
V_fixture_min= 0.0
V_fixture_max= 0.0
|time   V(typ)   V(min)   V(max)
0s        4.549nV    50.98nV    2.322nV
1.07ns    -34.28uV   10.15uV    1.547mV
1.678ns   -8.183mV   213uV      796.1mV
2.17ns    12.25mV    -1.044mV   946.8mV
2.443ns   145.6mV    -4.326mV   968.3mV
3.064ns   444.1mV    -3.566mV   985.1mV
4.229ns   559.3mV    27.27mV    990.1mV
5.412ns   573.8mV    268.3mV    990.5mV
6.574ns   576.5mV    347.3mV    990.6mV
20ns      577.2mV    368.8mV    990.6mV
[Rising Waveform]
R_fixture= 50.000
V_fixture= 1.500
V_fixture_min= 1.430
V_fixture_max= 1.580
|time   V(typ)   V(min)   V(max)
0s        927.7mV    1.105V     670.5mV
695ps     927.7mV    1.105V     667.5mV
851ps     927.5mV    1.105V     1.064V
999ps     927.7mV    1.105V     1.282V
1.365ns   943.4mV    1.105V     1.536V
1.616ns   1.281V     1.105V     1.563V
2.347ns   1.464V     1.094V     1.575V
2.842ns   1.489V     1.346V     1.576V
3.707ns   1.497V     1.411V     1.577V
20ns      1.498V     1.429V     1.577V
[Falling Waveform]
R_fixture= 50.000
V_fixture= 1.500
V_fixture_min= 1.430
V_fixture_max= 1.580
|time   V(typ)   V(min)   V(max)
0s        1.498V     1.429V     1.577V
840ps     1.498V     1.429V     1.621V
1.163ns   1.498V     1.429V     1.563V
1.999ns   1.502V     1.429V     919.3mV
2.514ns   1.457V     1.428V     753.1mV
3.117ns   1.273V     1.451V     692.8mV
4.06ns    1.049V     1.428V     673.7mV
5.547ns   947.1mV    1.341V     670.7mV
8.336ns   928.2mV    1.136V     670.5mV
20ns      927.7mV    1.105V     670.5mV
[Falling Waveform]
R_fixture= 50.000
V_fixture= 0.0
V_fixture_min= 0.0
V_fixture_max= 0.0
|time   V(typ)   V(min)   V(max)
0s        577.2mV    368.8mV    990.6mV
743ps     577.3mV    368.8mV    988.1mV
919ps     577.3mV    368.8mV    502.2mV
1.077ns   577.3mV    368.8mV    277.3mV
1.437ns   576.9mV    368.8mV    52.02mV
1.709ns   240.3mV    368.8mV    14.32mV
2.654ns   17.51mV    372.7mV    1.083mV
3.282ns   3.853mV    66.02mV    264.9uV
4.18ns    893.7uV    9.792mV    47.82uV
20ns      7.127nV    114.5nV    -10.93nV
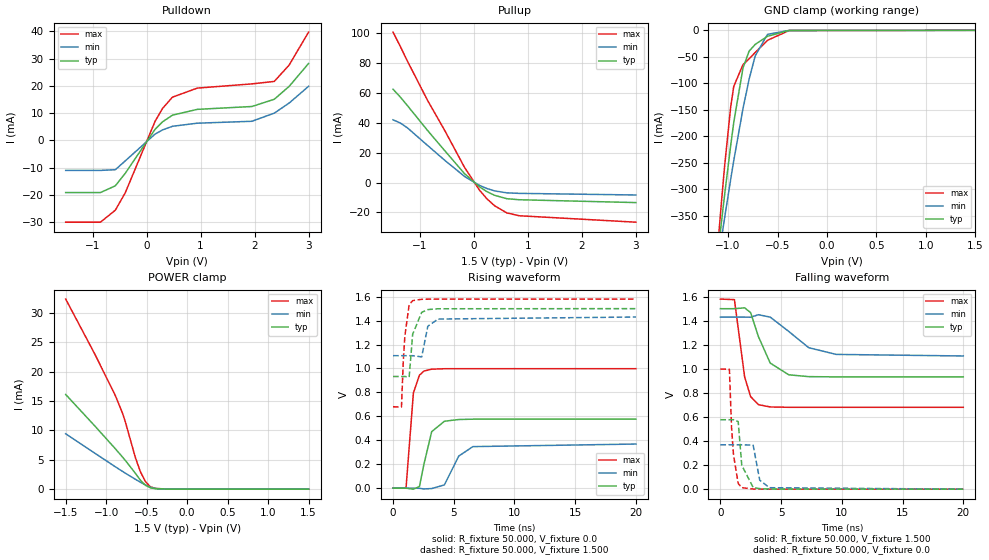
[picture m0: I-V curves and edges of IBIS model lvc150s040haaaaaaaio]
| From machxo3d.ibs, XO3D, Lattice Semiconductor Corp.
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|   Model lvc150s040haaaaaaaio
[Model] lvc150s040haaaaaaaio
Model_type I/O
Polarity   Non-Inverting
Enable   Active-Low
Vinl =  0.375V
Vinh =  1.125V
Vmeas =  0.750V
Cref =  0.0F
Rref =  1.000M
Vref =  0.0V
C_comp   4.200pF   3.800pF   7.500pF
[Temperature Range]   25.000   0.105k   -40.000
[Voltage Range]   1.500V   1.430V   1.580V
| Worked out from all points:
|   slope of the pulldown table from 0 to 0.225 V, typ, clamps not added: 40.7 ohm
|   slope of the pullup table from 0 to 0.225 V, typ, clamps not added: 38.9 ohm
|   GND clamp passes 1 mA (typ) near -0.43 V on its own axis
|   POWER clamp passes 1 mA (typ) near -0.54 V on its own axis
|   rising waveform, R_fixture 50.000, V_fixture 0.0: 20-80 % time 746ps typ, 1.18ns min, 446ps max; typ from 0 V to 0.577 V
|   rising waveform, R_fixture 50.000, V_fixture 1.500: 20-80 % time 365ps typ, 377ps min, 352ps max; typ from 0.933 V to 1.5 V
|   falling waveform, R_fixture 50.000, V_fixture 1.500: 20-80 % time 1.33ns typ, 2.25ns min, 756ps max; typ from 1.5 V to 0.933 V
|   falling waveform, R_fixture 50.000, V_fixture 0.0: 20-80 % time 383ps typ, 421ps min, 387ps max; typ from 0.577 V to 0 V
[Pulldown]
|Voltage   I(typ)   I(min)   I(max)
-1.5V     -19.1mA    -10.99mA   -29.96mA
-856mV    -19.1mA    -10.99mA   -29.96mA
-580mV    -16.64mA   -10.73mA   -25.56mA
-396mV    -12.04mA   -7.496mA   -19.19mA
156mV     4.064mA    2.312mA    6.984mA
294mV     6.796mA    3.838mA    11.69mA
478mV     9.247mA    5.168mA    15.84mA
938mV     11.37mA    6.303mA    19.16mA
1.95V     12.42mA    7.008mA    20.71mA
2.364V    15.07mA    9.98mA     21.6mA
2.64V     19.79mA    13.69mA    27.6mA
3V        28.19mA    19.81mA    39.68mA
[Pullup]
|Voltage   I(typ)   I(min)   I(max)
-1.5V     62.3mA     41.88mA    100.5mA
-1.37V    57.31mA    39.84mA    91.24mA
-1.232V   51.33mA    36.49mA    81.03mA
-864mV    34.92mA    24.88mA    55.09mA
-542mV    21.27mA    14.84mA    34.76mA
-174mV    5.857mA    4.015mA    10.01mA
102mV     -2.891mA   -1.927mA   -5.109mA
240mV     -6.098mA   -4.031mA   -10.91mA
378mV     -8.511mA   -5.568mA   -15.45mA
608mV     -10.83mA   -6.929mA   -20.32mA
838mV     -11.52mA   -7.262mA   -22.22mA
3V        -13.42mA   -8.343mA   -26.52mA
[GND_clamp]
|Voltage   I(typ)   I(min)   I(max)
-1.5V     -1.124A    -960.6mA   -1.411A
-1.097V   -411.6mA   -430.5mA   -393mA
-1.066V   -360.7mA   -392.1mA   -323mA
-1.035V   -311mA     -354.2mA   -256.8mA
-973mV    -216.9mA   -280.8mA   -144.3mA
-942mV    -173.5mA   -245.5mA   -105.7mA
-849mV    -71.09mA   -147.7mA   -64.66mA
-787mV    -39.21mA   -92.09mA   -53.75mA
-725mV    -26.45mA   -48.04mA   -41.65mA
-601mV    -11.21mA   -7.588mA   -18.81mA
-384mV    -319.8uA   -151.2uA   -484.4uA
1.5V      -41.68nA   0A         -8.283uA
[POWER_clamp]
|Voltage   I(typ)   I(min)   I(max)
-1.5V     16.13mA    9.435mA    32.38mA
-1.135V   10.69mA    6.084mA    22.87mA
-887mV    6.888mA    3.813mA    15.95mA
-794mV    5.406mA    2.992mA    12.8mA
-763mV    4.897mA    2.724mA    11.46mA
-639mV    2.697mA    1.677mA    5.367mA
-577mV    1.529mA    1.181mA    2.962mA
-515mV    656.7uA    722.8uA    1.279mA
-453mV    227.4uA    343.3uA    403.8uA
-391mV    80.76uA    114.4uA    122.7uA
-267mV    21.1uA     15.5uA     34.42uA
1.5V      0A         0A         0A
[Ramp]
| variable   typ   min   max
dV/dt_r   0.346/0.741n   0.221/1.189n   0.599/0.446n
dV/dt_f   0.340/1.349n   0.194/2.206n   0.540/0.759n
R_load = 50.000
[Rising Waveform]
R_fixture= 50.000
V_fixture= 0.0
V_fixture_min= 0.0
V_fixture_max= 0.0
|time   V(typ)   V(min)   V(max)
0s        4.549nV    50.98nV    2.322nV
1.07ns    -34.27uV   6.784uV    1.547mV
1.678ns   -8.183mV   221.2uV    796.1mV
2.175ns   13.56mV    -1.079mV   943.8mV
2.541ns   198.6mV    -6.263mV   978.2mV
3.183ns   472.3mV    -3.044mV   994.2mV
4.229ns   559.3mV    27.27mV    997.9mV
5.412ns   573.8mV    268.3mV    998.3mV
6.574ns   576.5mV    347.3mV    998.4mV
20ns      577.2mV    368.8mV    998.4mV
[Rising Waveform]
R_fixture= 50.000
V_fixture= 1.500
V_fixture_min= 1.430
V_fixture_max= 1.580
|time   V(typ)   V(min)   V(max)
0s        933mV      1.107V     680.4mV
695ps     933.1mV    1.107V     677.4mV
849ps     932.9mV    1.107V     1.072V
975ps     933mV      1.107V     1.271V
1.329ns   927.9mV    1.107V     1.533V
1.616ns   1.286V     1.107V     1.567V
2.36ns    1.469V     1.097V     1.578V
2.862ns   1.492V     1.353V     1.579V
3.712ns   1.499V     1.413V     1.58V
20ns      1.5V       1.43V      1.58V
[Falling Waveform]
R_fixture= 50.000
V_fixture= 1.500
V_fixture_min= 1.430
V_fixture_max= 1.580
|time   V(typ)   V(min)   V(max)
0s        1.5V       1.43V      1.58V
1.157ns   1.5V       1.43V      1.575V
1.997ns   1.507V     1.43V      932.5mV
2.491ns   1.467V     1.429V     769.2mV
3.135ns   1.267V     1.45V      702.5mV
4.104ns   1.048V     1.43V      683.2mV
5.628ns   950.6mV    1.311V     680.5mV
7.27ns    935.3mV    1.176V     680.4mV
9.537ns   933.2mV    1.12V      680.4mV
20ns      933mV      1.107V     680.4mV
[Falling Waveform]
R_fixture= 50.000
V_fixture= 0.0
V_fixture_min= 0.0
V_fixture_max= 0.0
|time   V(typ)   V(min)   V(max)
0s        577.2mV    368.8mV    998.4mV
743ps     577.3mV    368.8mV    996mV
919ps     577.3mV    368.8mV    513.3mV
1.08ns    577.3mV    368.8mV    285.8mV
1.465ns   562.2mV    368.8mV    47.93mV
1.761ns   198.3mV    368.8mV    12.66mV
2.696ns   14.89mV    366.1mV    926.5uV
3.242ns   4.245mV    74.66mV    293.7uV
4.036ns   1.104mV    12.09mV    62.63uV
20ns      7.127nV    114.5nV    -10nV
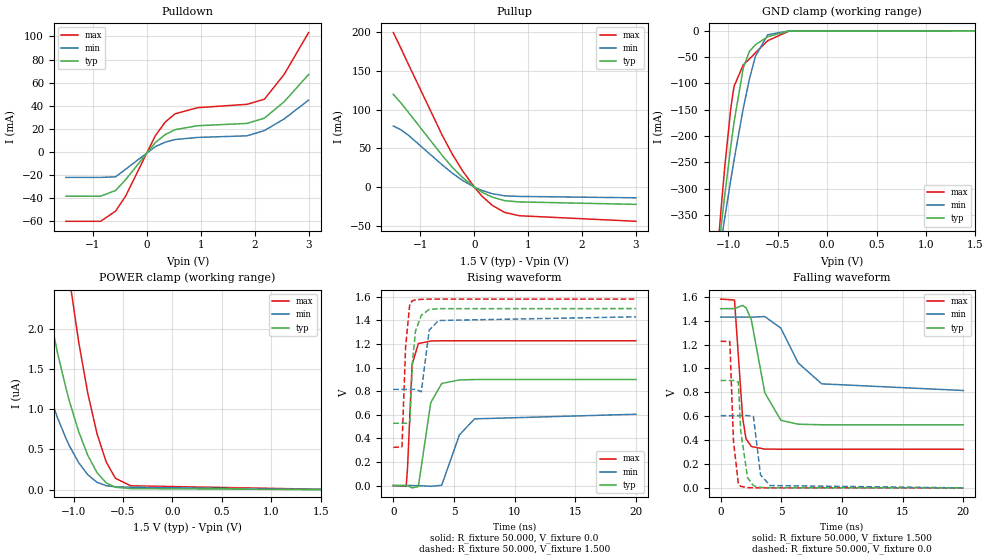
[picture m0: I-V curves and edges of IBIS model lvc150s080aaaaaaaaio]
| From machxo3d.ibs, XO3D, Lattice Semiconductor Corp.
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|   Model lvc150s080aaaaaaaaio
[Model] lvc150s080aaaaaaaaio
Model_type I/O
Polarity   Non-Inverting
Enable   Active-Low
Vinl =  0.375V
Vinh =  1.125V
Vmeas =  0.750V
Cref =  0.0F
Rref =  1.000M
Vref =  0.0V
C_comp   4.200pF   3.800pF   7.500pF
[Temperature Range]   25.000   0.105k   -40.000
[Voltage Range]   1.500V   1.430V   1.580V
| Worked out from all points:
|   slope of the pulldown table from 0 to 0.225 V, typ, clamps not added: 20.4 ohm
|   slope of the pullup table from 0 to 0.225 V, typ, clamps not added: 23.3 ohm
|   GND clamp passes 1 mA (typ) near -0.44 V on its own axis
|   rising waveform, R_fixture 50.000, V_fixture 0.0: 20-80 % time 734ps typ, 1.28ns min, 305ps max; typ from 0 V to 0.899 V
|   rising waveform, R_fixture 50.000, V_fixture 1.500: 20-80 % time 363ps typ, 375ps min, 348ps max; typ from 0.528 V to 1.5 V
|   falling waveform, R_fixture 50.000, V_fixture 1.500: 20-80 % time 1.16ns typ, 2.2ns min, 488ps max; typ from 1.5 V to 0.528 V
|   falling waveform, R_fixture 50.000, V_fixture 0.0: 20-80 % time 387ps typ, 423ps min, 361ps max; typ from 0.899 V to 0 V
[Pulldown]
|Voltage   I(typ)   I(min)   I(max)
-1.5V     -38.2mA    -21.99mA   -59.93mA
-856mV    -38.2mA    -21.99mA   -59.93mA
-580mV    -33.29mA   -21.45mA   -51.12mA
-396mV    -24.09mA   -14.99mA   -38.38mA
156mV     8.127mA    4.623mA    13.97mA
340mV     15.07mA    8.487mA    25.9mA
524mV     19.32mA    10.78mA    33.03mA
938mV     22.73mA    12.61mA    38.32mA
1.858V    24.74mA    13.99mA    41.25mA
2.18V     29.28mA    18.55mA    45.66mA
2.548V    43.52mA    28.65mA    67.2mA
3V        67.03mA    44.9mA     103.3mA
[Pullup]
|Voltage   I(typ)   I(min)   I(max)
-1.5V     119.6mA    78.77mA    199.4mA
-1.37V    109.5mA    74.31mA    180.8mA
-1.232V   97.48mA    67.55mA    160.2mA
-588mV    40.38mA    28.31mA    66.15mA
-404mV    25.37mA    17.83mA    42.21mA
-220mV    12.63mA    8.708mA    21.47mA
10mV      -505.5uA   -338.4uA   -886.9uA
148mV     -6.75mA    -4.487mA   -11.97mA
332mV     -12.99mA   -8.529mA   -23.46mA
562mV     -17.55mA   -11.28mA   -32.68mA
838mV     -19.2mA    -12.1mA    -37.04mA
3V        -22.36mA   -13.9mA    -44.21mA
[GND_clamp]
|Voltage   I(typ)   I(min)   I(max)
-1.5V     -1.124A    -960.6mA   -1.411A
-1.097V   -411.6mA   -430.5mA   -392.9mA
-1.066V   -360.7mA   -392.1mA   -323mA
-1.035V   -311mA     -354.2mA   -256.7mA
-973mV    -216.8mA   -280.8mA   -144.2mA
-942mV    -173.4mA   -245.5mA   -105.6mA
-849mV    -71.05mA   -147.7mA   -64.59mA
-787mV    -39.16mA   -92.07mA   -53.68mA
-725mV    -26.4mA    -48.02mA   -41.58mA
-601mV    -11.15mA   -7.544mA   -18.72mA
-384mV    -236.4uA   -103.3uA   -351.1uA
1.5V      0A         0A         0A
[POWER_clamp]
|Voltage   I(typ)   I(min)   I(max)
-1.5V     4.017uA    2.297uA    8.486uA
-1.321V   2.676uA    1.475uA    5.815uA
-1.166V   1.719uA    902.9nA    3.892uA
-1.073V   1.242uA    625.4nA    2.92uA
-1.042V   1.099uA    544.2nA    2.626uA
-949mV    723.1nA    335.9nA    1.84uA
-856mV    425.6nA    184nA      1.196uA
-763mV    211.1nA    90.96nA    695.6nA
-670mV    83.05nA    48.44nA    343.1nA
-577mV    29.4nA     34.63nA    141.1nA
-422mV    12.85nA    29.52nA    47.31nA
1.5V      0A         0A         4.131nA
[Ramp]
| variable   typ   min   max
dV/dt_r   0.540/0.734n   0.363/1.282n   0.736/0.304n
dV/dt_f   0.583/1.160n   0.369/2.194n   0.754/0.489n
R_load = 50.000
[Rising Waveform]
R_fixture= 50.000
V_fixture= 0.0
V_fixture_min= 0.0
V_fixture_max= 0.0
|time   V(typ)   V(min)   V(max)
0s        2.959nV    35.35nV    1.474nV
1.062ns   -115.1uV   3.093uV    -5.7mV
1.172ns   -965.2uV   3.093uV    146.7mV
1.547ns   -19.55mV   99.14uV    1.024V
2.063ns   -8.774mV   -555.3uV   1.203V
3.087ns   703mV      -6.198mV   1.225V
3.99ns    865.1mV    2.39mV     1.227V
5.449ns   895.3mV    429.7mV    1.227V
6.699ns   898.4mV    565.2mV    1.227V
20ns      899.2mV    604.4mV    1.227V
[Rising Waveform]
R_fixture= 50.000
V_fixture= 1.500
V_fixture_min= 1.430
V_fixture_max= 1.580
|time   V(typ)   V(min)   V(max)
0s        527.9mV    815.2mV    323.4mV
714ps     527.9mV    815.2mV    327.9mV
1.014ns   527.5mV    815.2mV    1.176V
1.357ns   533.8mV    815.1mV    1.539V
1.581ns   1.047V     814.6mV    1.567V
1.826ns   1.309V     815.2mV    1.574V
2.308ns   1.443V     794.8mV    1.578V
2.958ns   1.493V     1.318V     1.58V
3.74ns    1.499V     1.399V     1.58V
20ns      1.5V       1.43V      1.58V
[Falling Waveform]
R_fixture= 50.000
V_fixture= 1.500
V_fixture_min= 1.430
V_fixture_max= 1.580
|time   V(typ)   V(min)   V(max)
0s        1.5V       1.43V      1.58V
1.14ns    1.501V     1.43V      1.573V
1.812ns   1.528V     1.43V      585.3mV
2.086ns   1.509V     1.43V      411.2mV
2.526ns   1.408V     1.429V     346.4mV
3.637ns   796.7mV    1.434V     324.7mV
4.963ns   565.6mV    1.337V     323.5mV
6.38ns    533mV      1.047V     323.4mV
8.332ns   528.1mV    870.7mV    323.4mV
20ns      527.7mV    815.2mV    323.4mV
[Falling Waveform]
R_fixture= 50.000
V_fixture= 0.0
V_fixture_min= 0.0
V_fixture_max= 0.0
|time   V(typ)   V(min)   V(max)
0s        899.2mV    604.4mV    1.227V
755ps     899.2mV    604.4mV    1.225V
1.058ns   899.3mV    604.4mV    388mV
1.459ns   886.3mV    604.4mV    34.42mV
1.65ns    480.4mV    604.4mV    12.25mV
2.215ns   84.34mV    604.8mV    2.018mV
2.7ns     18.62mV    598.6mV    604.9uV
3.286ns   4.012mV    108mV      132.4uV
4.076ns   991.2uV    19.37mV    32.53uV
20ns      7.195nV    97.15nV    -7.209nV
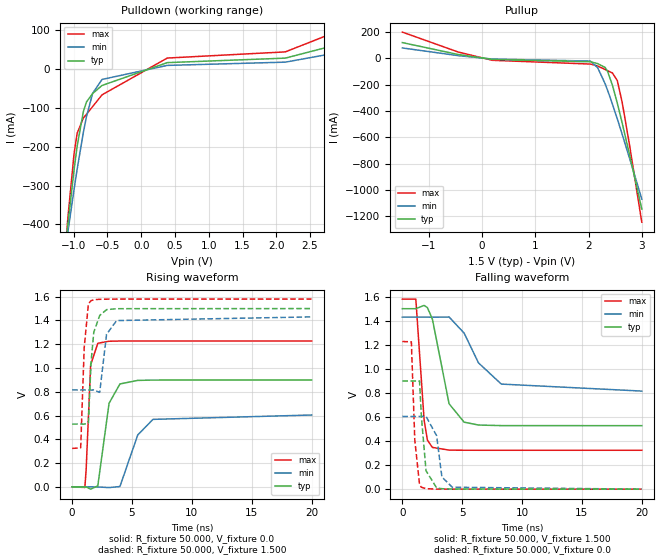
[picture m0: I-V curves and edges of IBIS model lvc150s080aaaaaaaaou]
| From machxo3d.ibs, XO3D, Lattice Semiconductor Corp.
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|   Model lvc150s080aaaaaaaaou
[Model] lvc150s080aaaaaaaaou
Model_type Output
Polarity   Non-Inverting
Enable   Active-High
Vmeas =  0.750V
Cref =  0.0F
Rref =  1.000M
Vref =  0.0V
C_comp   4.200pF   3.800pF   7.500pF
[Temperature Range]   25.000   0.105k   -40.000
[Voltage Range]   1.500V   1.430V   1.580V
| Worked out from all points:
|   slope of the pulldown table from 0 to 0.225 V, typ, clamps not added: 20.4 ohm
|   slope of the pullup table from 0 to 0.225 V, typ, clamps not added: 23.3 ohm
|   rising waveform, R_fixture 50.000, V_fixture 0.0: 20-80 % time 736ps typ, 1.27ns min, 305ps max; typ from 0 V to 0.899 V
|   rising waveform, R_fixture 50.000, V_fixture 1.500: 20-80 % time 363ps typ, 376ps min, 347ps max; typ from 0.528 V to 1.5 V
|   falling waveform, R_fixture 50.000, V_fixture 1.500: 20-80 % time 1.15ns typ, 2.19ns min, 484ps max; typ from 1.5 V to 0.528 V
|   falling waveform, R_fixture 50.000, V_fixture 0.0: 20-80 % time 386ps typ, 421ps min, 359ps max; typ from 0.899 V to 0 V
[Pulldown]
|Voltage   I(typ)   I(min)   I(max)
-1.5V     -1.126A    -962mA     -1.414A
-1.132V   -475.7mA   -477.5mA   -486mA
-1.086V   -400.2mA   -420.1mA   -383.6mA
-994mV    -259.5mA   -309.7mA   -217.9mA
-948mV    -198.4mA   -257.5mA   -165.3mA
-856mV    -109.3mA   -162.8mA   -125.9mA
-810mV    -84.86mA   -122.4mA   -116.6mA
-718mV    -62.87mA   -62.28mA   -96.47mA
-580mV    -42.42mA   -26.88mA   -66.58mA
386mV     16.37mA    9.198mA    28.13mA
2.134V    27.94mA    17.58mA    44.01mA
3V        67.03mA    44.9mA     103.3mA
[Pullup]
|Voltage   I(typ)   I(min)   I(max)
-1.5V     119.6mA    78.77mA    199.4mA
-450mV    28.89mA    20.36mA    47.84mA
194mV     -8.531mA   -5.655mA   -15.19mA
2.034V    -26.4mA    -21.05mA   -43.62mA
2.172V    -40.46mA   -72.01mA   -59.08mA
2.31V     -69.15mA   -192.2mA   -84.81mA
2.356V    -98.37mA   -241.2mA   -93.99mA
2.448V    -203.4mA   -347.3mA   -111mA
2.54V     -340.8mA   -460.5mA   -169.2mA
2.632V    -492.2mA   -577.9mA   -335.7mA
2.77V     -731.7mA   -759.3mA   -659.4mA
3V        -1.146A    -1.07A     -1.246A
[Ramp]
| variable   typ   min   max
dV/dt_r   0.540/0.733n   0.363/1.281n   0.736/0.303n
dV/dt_f   0.583/1.160n   0.369/2.190n   0.754/0.488n
R_load = 50.000
[Rising Waveform]
R_fixture= 50.000
V_fixture= 0.0
V_fixture_min= 0.0
V_fixture_max= 0.0
|time   V(typ)   V(min)   V(max)
0s        2.932nV    35.47nV    1.446nV
1.063ns   -116.2uV   2.858uV    -5.173mV
1.171ns   -891.1uV   2.858uV    144.7mV
1.548ns   -19.58mV   100.1uV    1.027V
2.145ns   8.305mV    -1.035mV   1.208V
3.085ns   703.1mV    -6.155mV   1.225V
3.991ns   865.6mV    2.484mV    1.227V
5.482ns   895.6mV    437mV      1.227V
6.755ns   898.4mV    567.7mV    1.227V
20ns      899.2mV    604.4mV    1.227V
[Rising Waveform]
R_fixture= 50.000
V_fixture= 1.500
V_fixture_min= 1.430
V_fixture_max= 1.580
|time   V(typ)   V(min)   V(max)
0s        527.9mV    815.2mV    323.4mV
714ps     527.9mV    815.2mV    327.9mV
1.01ns    527.5mV    815.2mV    1.173V
1.361ns   537.1mV    815mV      1.54V
1.583ns   1.051V     814.6mV    1.567V
1.809ns   1.301V     815.1mV    1.574V
2.304ns   1.442V     794.9mV    1.578V
2.878ns   1.491V     1.284V     1.579V
3.715ns   1.499V     1.399V     1.58V
20ns      1.5V       1.43V      1.58V
[Falling Waveform]
R_fixture= 50.000
V_fixture= 1.500
V_fixture_min= 1.430
V_fixture_max= 1.580
|time   V(typ)   V(min)   V(max)
0s        1.5V       1.43V      1.58V
1.129ns   1.5V       1.43V      1.579V
1.822ns   1.527V     1.43V      574mV
2.095ns   1.509V     1.43V      407.5mV
2.514ns   1.413V     1.429V     347mV
3.906ns   709.9mV    1.431V     324.4mV
5.163ns   556.7mV    1.297V     323.5mV
6.359ns   533mV      1.05V      323.4mV
8.267ns   528.3mV    873.4mV    323.4mV
20ns      527.7mV    815.2mV    323.4mV
[Falling Waveform]
R_fixture= 50.000
V_fixture= 0.0
V_fixture_min= 0.0
V_fixture_max= 0.0
|time   V(typ)   V(min)   V(max)
0s        899.2mV    604.4mV    1.227V
755ps     899.2mV    604.4mV    1.225V
1.042ns   899.2mV    604.4mV    408.9mV
1.437ns   899.7mV    604.4mV    39.49mV
1.593ns   602.8mV    604.4mV    15.53mV
1.982ns   152.9mV    605.1mV    4.165mV
2.865ns   10.68mV    444.2mV    428uV
3.306ns   3.814mV    101.2mV    120.8uV
4.173ns   855.8uV    16.18mV    28.42uV
20ns      54.37nV    97.53nV    14.48nV
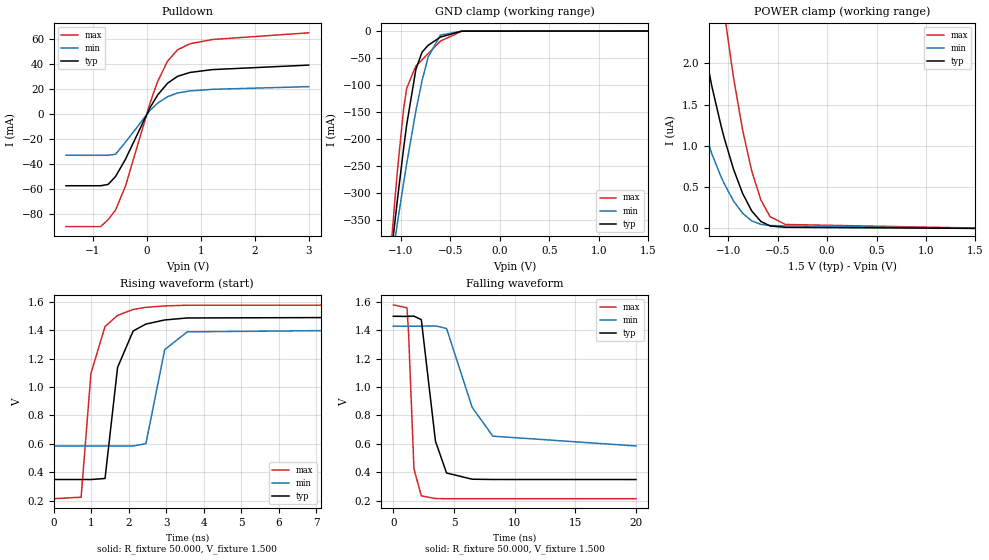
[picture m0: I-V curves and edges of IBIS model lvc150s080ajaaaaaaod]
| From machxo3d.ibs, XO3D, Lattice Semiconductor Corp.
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|   Model lvc150s080ajaaaaaaod
[Model] lvc150s080ajaaaaaaod
Model_type I/O_open_drain
Polarity   Non-Inverting
Enable   Active-Low
Vinl =  0.375V
Vinh =  1.125V
Vmeas =  0.750V
Cref =  0.0F
Rref = 10.00k
Vref = 1.50V
C_comp   4.200pF   3.800pF   7.500pF
[Temperature Range]   25.000   0.105k   -40.000
[Voltage Range]   1.500V   1.430V   1.580V
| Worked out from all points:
|   slope of the pulldown table from 0 to 0.225 V, typ, clamps not added: 13.6 ohm
|   GND clamp passes 1 mA (typ) near -0.44 V on its own axis
|   rising waveform, R_fixture 50.000, V_fixture 1.500: 20-80 % time 347ps typ, 372ps min, 349ps max; typ from 0.348 V to 1.5 V
|   falling waveform, R_fixture 50.000, V_fixture 1.500: 20-80 % time 908ps typ, 2.09ns min, 368ps max; typ from 1.5 V to 0.348 V
[Pulldown]
|Voltage   I(typ)   I(min)   I(max)
-1.5V     -57.3mA    -32.98mA   -89.89mA
-856mV    -57.3mA    -32.98mA   -89.89mA
-718mV    -56.25mA   -32.98mA   -84.39mA
-580mV    -49.93mA   -32.18mA   -76.68mA
-396mV    -36.13mA   -22.49mA   -57.56mA
64mV      5.387mA    3.076mA    9.254mA
202mV     15.19mA    8.62mA     26.11mA
386mV     24.56mA    13.8mA     42.19mA
570mV     30.02mA    16.71mA    51.2mA
800mV     33.11mA    18.37mA    55.99mA
1.214V    35.37mA    19.63mA    59.38mA
3V        38.96mA    21.78mA    64.73mA
[GND_clamp]
|Voltage   I(typ)   I(min)   I(max)
-1.5V     -1.124A    -960.6mA   -1.411A
-1.097V   -411.6mA   -430.5mA   -392.9mA
-1.066V   -360.7mA   -392.1mA   -323mA
-1.035V   -311mA     -354.2mA   -256.8mA
-973mV    -216.9mA   -280.8mA   -144.3mA
-942mV    -173.5mA   -245.5mA   -105.7mA
-849mV    -71.07mA   -147.7mA   -64.62mA
-787mV    -39.18mA   -92.07mA   -53.7mA
-725mV    -26.42mA   -48.02mA   -41.6mA
-601mV    -11.16mA   -7.547mA   -18.74mA
-384mV    -237.5uA   -103.4uA   -356uA
1.5V      0A         0A         0A
[POWER_clamp]
|Voltage   I(typ)   I(min)   I(max)
-1.5V     4.017uA    2.297uA    8.486uA
-1.321V   2.676uA    1.475uA    5.815uA
-1.166V   1.719uA    902.9nA    3.892uA
-1.073V   1.242uA    625.4nA    2.92uA
-1.042V   1.099uA    544.2nA    2.626uA
-949mV    723.1nA    335.9nA    1.84uA
-856mV    425.6nA    184nA      1.196uA
-763mV    211.1nA    90.96nA    695.5nA
-670mV    83.03nA    48.43nA    343.1nA
-577mV    29.38nA    34.63nA    141nA
-422mV    12.83nA    29.52nA    47.27nA
1.5V      0A         0A         4.136nA
[Ramp]
| variable   typ   min   max
dV/dt_r   0.691/0.346n   0.507/0.373n   0.820/0.349n
dV/dt_f   0.691/0.912n   0.507/2.061n   0.820/0.367n
R_load = 50.000
[Rising Waveform]
R_fixture= 50.000
V_fixture= 1.500
V_fixture_min= 1.430
V_fixture_max= 1.580
|time   V(typ)   V(min)   V(max)
0s        348.1mV    585.1mV    212.8mV
728ps     348.1mV    585.1mV    223.5mV
990ps     348mV      585.1mV    1.097V
1.366ns   355.4mV    584.9mV    1.428V
1.7ns     1.139V     584.5mV    1.506V
2.115ns   1.396V     584.9mV    1.548V
2.455ns   1.445V     600.8mV    1.563V
2.958ns   1.474V     1.265V     1.573V
3.559ns   1.488V     1.39V      1.578V
20ns      1.5V       1.43V      1.58V
[Falling Waveform]
R_fixture= 50.000
V_fixture= 1.500
V_fixture_min= 1.430
V_fixture_max= 1.580
|time   V(typ)   V(min)   V(max)
0s        1.5V       1.43V      1.58V
1.126ns   1.499V     1.43V      1.56V
1.257ns   1.5V       1.43V      1.384V
1.701ns   1.501V     1.43V      423.6mV
2.308ns   1.476V     1.43V      233mV
3.475ns   618.4mV    1.432V     213.8mV
4.388ns   394.3mV    1.414V     212.8mV
6.5ns     350.2mV    857.3mV    212.8mV
8.205ns   348.3mV    654mV      212.8mV
20ns      348mV      584.9mV    212.8mV
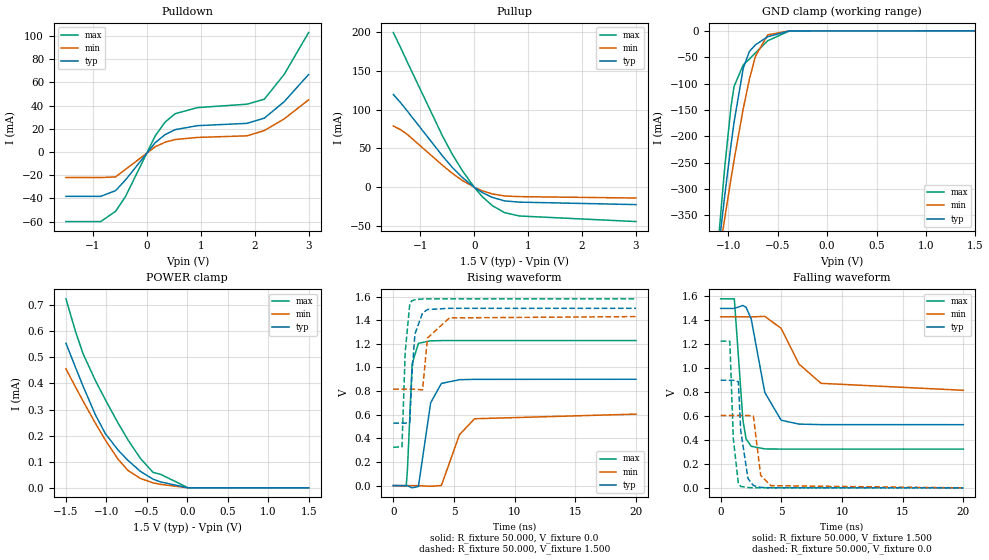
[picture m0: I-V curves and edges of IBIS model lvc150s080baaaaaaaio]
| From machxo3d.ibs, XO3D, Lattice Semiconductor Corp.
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|   Model lvc150s080baaaaaaaio
[Model] lvc150s080baaaaaaaio
Model_type I/O
Polarity   Non-Inverting
Enable   Active-Low
Vinl =  0.375V
Vinh =  1.125V
Vmeas =  0.750V
Cref =  0.0F
Rref =  1.000M
Vref =  0.0V
C_comp   4.200pF   3.800pF   7.500pF
[Temperature Range]   25.000   0.105k   -40.000
[Voltage Range]   1.500V   1.430V   1.580V
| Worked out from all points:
|   slope of the pulldown table from 0 to 0.225 V, typ, clamps not added: 20.4 ohm
|   slope of the pullup table from 0 to 0.225 V, typ, clamps not added: 23.3 ohm
|   GND clamp passes 1 mA (typ) near -0.44 V on its own axis
|   rising waveform, R_fixture 50.000, V_fixture 0.0: 20-80 % time 732ps typ, 1.28ns min, 304ps max; typ from 0 V to 0.9 V
|   rising waveform, R_fixture 50.000, V_fixture 1.500: 20-80 % time 364ps typ, 376ps min, 346ps max; typ from 0.529 V to 1.5 V
|   falling waveform, R_fixture 50.000, V_fixture 1.500: 20-80 % time 1.16ns typ, 2.16ns min, 490ps max; typ from 1.5 V to 0.528 V
|   falling waveform, R_fixture 50.000, V_fixture 0.0: 20-80 % time 388ps typ, 424ps min, 361ps max; typ from 0.9 V to 0 V
[Pulldown]
|Voltage   I(typ)   I(min)   I(max)
-1.5V     -38.2mA    -21.99mA   -59.93mA
-856mV    -38.2mA    -21.99mA   -59.93mA
-580mV    -33.29mA   -21.45mA   -51.12mA
-396mV    -24.09mA   -14.99mA   -38.38mA
156mV     8.127mA    4.623mA    13.97mA
340mV     15.07mA    8.487mA    25.9mA
524mV     19.32mA    10.78mA    33.03mA
938mV     22.73mA    12.61mA    38.32mA
1.858V    24.74mA    13.98mA    41.25mA
2.18V     29.24mA    18.53mA    45.59mA
2.548V    43.44mA    28.61mA    67.01mA
3V        66.87mA    45mA       103mA
[Pullup]
|Voltage   I(typ)   I(min)   I(max)
-1.5V     119.5mA    78.9mA     199.2mA
-1.37V    109.3mA    74.35mA    180.6mA
-1.232V   97.37mA    67.54mA    160mA
-588mV    40.35mA    28.3mA     66.08mA
-404mV    25.36mA    17.82mA    42.19mA
-220mV    12.63mA    8.708mA    21.47mA
10mV      -505.5uA   -338.4uA   -886.9uA
148mV     -6.75mA    -4.487mA   -11.97mA
332mV     -12.99mA   -8.529mA   -23.46mA
562mV     -17.55mA   -11.28mA   -32.68mA
838mV     -19.2mA    -12.1mA    -37.04mA
3V        -22.36mA   -13.9mA    -44.21mA
[GND_clamp]
|Voltage   I(typ)   I(min)   I(max)
-1.5V     -1.124A    -960.6mA   -1.411A
-1.097V   -411.6mA   -430.5mA   -392.9mA
-1.066V   -360.7mA   -392.1mA   -323mA
-1.035V   -311mA     -354.2mA   -256.7mA
-973mV    -216.8mA   -280.8mA   -144.3mA
-942mV    -173.5mA   -245.5mA   -105.7mA
-849mV    -71.06mA   -147.7mA   -64.61mA
-787mV    -39.17mA   -92.07mA   -53.7mA
-725mV    -26.41mA   -48.02mA   -41.6mA
-601mV    -11.16mA   -7.552mA   -18.74mA
-384mV    -258.6uA   -114.9uA   -396.2uA
1.5V      -41.68nA   0A         -8.283uA
[POWER_clamp]
|Voltage   I(typ)   I(min)   I(max)
-1.5V     553.8uA    455.7uA    723.9uA
-1.383V   462uA      386.8uA    600.3uA
-1.29V    390.6uA    333.2uA    514.8uA
-1.135V   279.1uA    247uA      410.2uA
-1.011V   206.7uA    182uA      336.5uA
-856mV    145uA      109.7uA    248.3uA
-732mV    104.8uA    66.29uA    183.2uA
-577mV    62.52uA    35.6uA     111.7uA
-422mV    33.03uA    19.13uA    58.98uA
-329mV    22.6uA     13.31uA    51.73uA
12mV      0A         0A         0A
1.5V      0A         0A         0A
[Ramp]
| variable   typ   min   max
dV/dt_r   0.540/0.732n   0.363/1.282n   0.736/0.304n
dV/dt_f   0.583/1.164n   0.369/2.182n   0.754/0.490n
R_load = 50.000
[Rising Waveform]
R_fixture= 50.000
V_fixture= 0.0
V_fixture_min= 0.0
V_fixture_max= 0.0
|time   V(typ)   V(min)   V(max)
0s        304.8uV    218.6uV    443.3uV
1.063ns   191.7uV    222.2uV    -3.144mV
1.169ns   -552.7uV   222.2uV    142.4mV
1.552ns   -18.88mV   318.7uV    1.031V
2.07ns    -6.937mV   -340.7uV   1.204V
3.08ns    701.1mV    -5.696mV   1.225V
3.963ns   864.5mV    786.3uV    1.227V
5.452ns   896mV      430.8mV    1.227V
6.699ns   899.1mV    565.7mV    1.227V
20ns      899.9mV    604.9mV    1.227V
[Rising Waveform]
R_fixture= 50.000
V_fixture= 1.500
V_fixture_min= 1.430
V_fixture_max= 1.580
|time   V(typ)   V(min)   V(max)
0s        528.5mV    815.7mV    324.1mV
714ps     528.5mV    815.7mV    328.7mV
980ps     528.2mV    815.7mV    1.129V
1.359ns   536.1mV    815.5mV    1.54V
1.528ns   929.7mV    815.5mV    1.563V
1.782ns   1.283V     815.4mV    1.573V
2.41ns    1.461V     810.1mV    1.579V
2.818ns   1.49V      1.249V     1.58V
4.629ns   1.5V       1.419V     1.58V
20ns      1.5V       1.43V      1.58V
[Falling Waveform]
R_fixture= 50.000
V_fixture= 1.500
V_fixture_min= 1.430
V_fixture_max= 1.580
|time   V(typ)   V(min)   V(max)
0s        1.5V       1.43V      1.58V
1.127ns   1.5V       1.43V      1.58V
1.835ns   1.525V     1.43V      564.2mV
2.095ns   1.509V     1.43V      409.6mV
2.515ns   1.413V     1.429V     347.9mV
3.638ns   797.4mV    1.434V     325.6mV
4.985ns   565.4mV    1.333V     324.2mV
6.458ns   533.1mV    1.035V     324.1mV
8.27ns    528.8mV    873.9mV    324.1mV
20ns      528.3mV    815.7mV    324.1mV
[Falling Waveform]
R_fixture= 50.000
V_fixture= 0.0
V_fixture_min= 0.0
V_fixture_max= 0.0
|time   V(typ)   V(min)   V(max)
0s        899.9mV    604.9mV    1.227V
755ps     900mV      605mV      1.225V
1.043ns   900mV      605mV      411.1mV
1.459ns   887.1mV    605mV      35.41mV
1.649ns   483.4mV    605mV      12.89mV
2.25ns    78.79mV    605.1mV    2.555mV
2.697ns   19.56mV    600.4mV    1.102mV
3.299ns   4.233mV    104.5mV    600.1uV
4.136ns   1.238mV    18.34mV    486.1uV
20ns      304.7uV    218.7uV    443.3uV
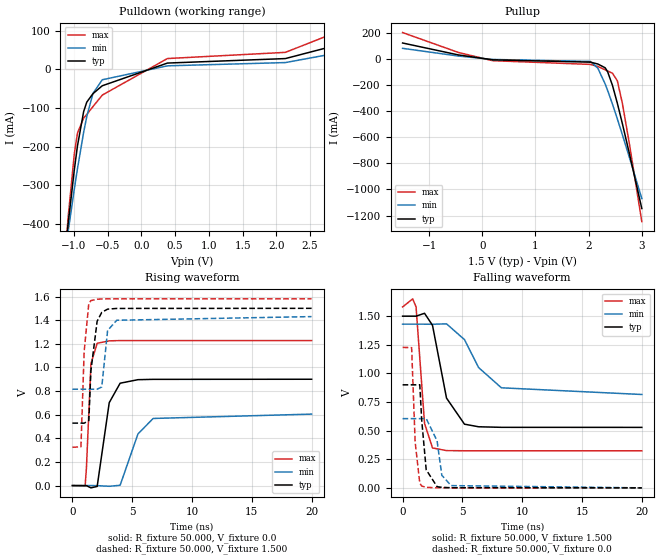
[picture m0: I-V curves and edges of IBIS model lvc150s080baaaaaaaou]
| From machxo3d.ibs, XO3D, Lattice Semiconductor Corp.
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|   Model lvc150s080baaaaaaaou
[Model] lvc150s080baaaaaaaou
Model_type Output
Polarity   Non-Inverting
Enable   Active-High
Vmeas =  0.750V
Cref =  0.0F
Rref =  1.000M
Vref =  0.0V
C_comp   4.200pF   3.800pF   7.500pF
[Temperature Range]   25.000   0.105k   -40.000
[Voltage Range]   1.500V   1.430V   1.580V
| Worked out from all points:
|   slope of the pulldown table from 0 to 0.225 V, typ, clamps not added: 20.4 ohm
|   slope of the pullup table from 0 to 0.225 V, typ, clamps not added: 23.3 ohm
|   rising waveform, R_fixture 50.000, V_fixture 0.0: 20-80 % time 732ps typ, 1.28ns min, 302ps max; typ from 0 V to 0.9 V
|   rising waveform, R_fixture 50.000, V_fixture 1.500: 20-80 % time 365ps typ, 373ps min, 347ps max; typ from 0.529 V to 1.5 V
|   falling waveform, R_fixture 50.000, V_fixture 1.500: 20-80 % time 1.17ns typ, 2.18ns min, 487ps max; typ from 1.5 V to 0.528 V
|   falling waveform, R_fixture 50.000, V_fixture 0.0: 20-80 % time 387ps typ, 421ps min, 359ps max; typ from 0.9 V to 0 V
[Pulldown]
|Voltage   I(typ)   I(min)   I(max)
-1.5V     -1.126A    -962mA     -1.414A
-1.132V   -475.7mA   -477.5mA   -486mA
-1.086V   -400.2mA   -420.1mA   -383.6mA
-994mV    -259.5mA   -309.7mA   -217.9mA
-948mV    -198.4mA   -257.5mA   -165.4mA
-856mV    -109.3mA   -162.8mA   -125.9mA
-810mV    -84.87mA   -122.4mA   -116.7mA
-718mV    -62.88mA   -62.28mA   -96.49mA
-580mV    -42.43mA   -26.88mA   -66.6mA
386mV     16.35mA    9.186mA    28.07mA
2.134V    27.98mA    17.63mA    44.05mA
3V        67.42mA    45.5mA     103.7mA
[Pullup]
|Voltage   I(typ)   I(min)   I(max)
-1.5V     120.1mA    79.35mA    199.9mA
-450mV    28.91mA    20.38mA    47.88mA
194mV     -8.541mA   -5.66mA    -15.21mA
2.034V    -26.41mA   -21.06mA   -43.66mA
2.172V    -40.47mA   -72.01mA   -59.1mA
2.31V     -69.15mA   -192.2mA   -84.82mA
2.356V    -98.37mA   -241.2mA   -94mA
2.448V    -203.4mA   -347.3mA   -111mA
2.54V     -340.9mA   -460.5mA   -169.2mA
2.632V    -492.2mA   -577.9mA   -335.8mA
2.77V     -731.7mA   -759.3mA   -659.4mA
3V        -1.146A    -1.07A     -1.246A
[Ramp]
| variable   typ   min   max
dV/dt_r   0.540/0.734n   0.363/1.281n   0.736/0.303n
dV/dt_f   0.583/1.160n   0.369/2.190n   0.754/0.489n
R_load = 50.000
[Rising Waveform]
R_fixture= 50.000
V_fixture= 0.0
V_fixture_min= 0.0
V_fixture_max= 0.0
|time   V(typ)   V(min)   V(max)
0s        304.8uV    218.6uV    443.3uV
1.063ns   190.6uV    221.5uV    -3.197mV
1.171ns   -576.7uV   221.5uV    146.7mV
1.552ns   -18.93mV   319.7uV    1.033V
2.07ns    -6.937mV   -340uV     1.204V
3.08ns    702.1mV    -5.751mV   1.225V
3.99ns    866.4mV    2.968mV    1.227V
5.48ns    896.3mV    437.1mV    1.227V
6.751ns   899.1mV    568.2mV    1.227V
20ns      899.9mV    604.9mV    1.227V
[Rising Waveform]
R_fixture= 50.000
V_fixture= 1.500
V_fixture_min= 1.430
V_fixture_max= 1.580
|time   V(typ)   V(min)   V(max)
0s        528.5mV    815.7mV    324.1mV
714ps     528.6mV    815.7mV    328.6mV
982ps     528.2mV    815.7mV    1.134V
1.373ns   549.5mV    815.5mV    1.544V
1.544ns   969.1mV    815.5mV    1.565V
2.068ns   1.391V     815.5mV    1.577V
2.455ns   1.466V     834.9mV    1.579V
2.943ns   1.493V     1.313V     1.58V
3.71ns    1.499V     1.399V     1.58V
20ns      1.5V       1.43V      1.58V
[Falling Waveform]
R_fixture= 50.000
V_fixture= 1.500
V_fixture_min= 1.430
V_fixture_max= 1.580
|time   V(typ)   V(min)   V(max)
0s        1.5V       1.43V      1.58V
844ps     1.5V       1.43V      1.651V
1.127ns   1.5V       1.43V      1.58V
1.835ns   1.525V     1.43V      563.2mV
2.501ns   1.42V      1.429V     348.8mV
3.673ns   784.1mV    1.433V     325.5mV
5.175ns   556.3mV    1.295V     324.1mV
6.355ns   533.7mV    1.051V     324.1mV
8.261ns   528.9mV    874.2mV    324.1mV
20ns      528.4mV    815.7mV    324.1mV
[Falling Waveform]
R_fixture= 50.000
V_fixture= 0.0
V_fixture_min= 0.0
V_fixture_max= 0.0
|time   V(typ)   V(min)   V(max)
0s        899.9mV    604.9mV    1.227V
755ps     900mV      605mV      1.225V
1.049ns   900mV      605mV      401.6mV
1.437ns   900.5mV    605mV      40.87mV
1.599ns   589.5mV    605mV      15.71mV
1.974ns   157.8mV    605.4mV    4.608mV
2.884ns   10.63mV    410.6mV    864.7uV
3.28ns    4.528mV    110.2mV    638.5uV
4.056ns   1.372mV    19.72mV    504.6uV
20ns      304.8uV    218.7uV    443.3uV
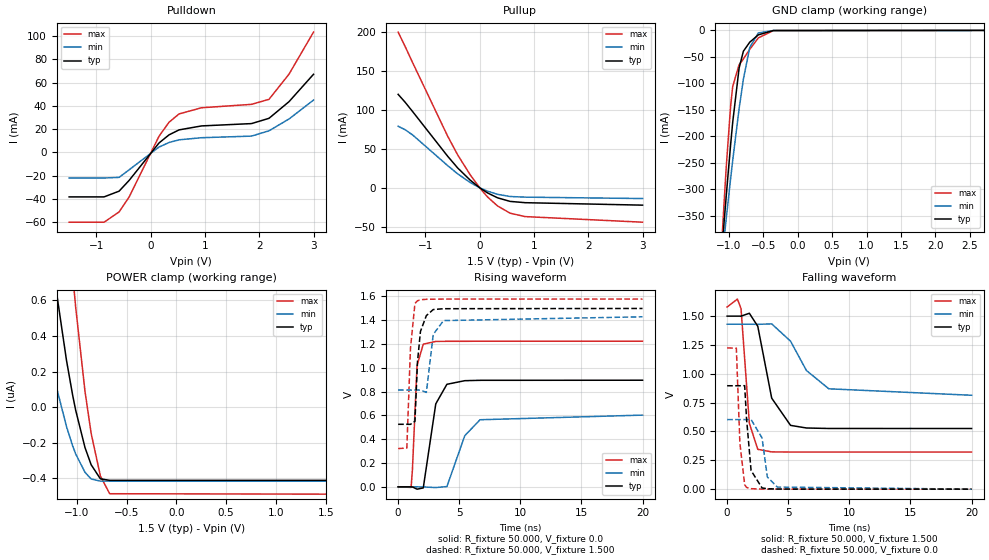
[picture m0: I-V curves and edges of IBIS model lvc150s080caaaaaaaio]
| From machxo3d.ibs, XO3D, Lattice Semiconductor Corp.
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|   Model lvc150s080caaaaaaaio
[Model] lvc150s080caaaaaaaio
Model_type I/O
Polarity   Non-Inverting
Enable   Active-Low
Vinl =  0.375V
Vinh =  1.125V
Vmeas =  0.750V
Cref =  0.0F
Rref =  1.000M
Vref =  0.0V
C_comp   4.200pF   3.800pF   7.500pF
[Temperature Range]   25.000   0.105k   -40.000
[Voltage Range]   1.500V   1.430V   1.580V
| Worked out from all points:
|   slope of the pulldown table from 0 to 0.225 V, typ, clamps not added: 20.4 ohm
|   slope of the pullup table from 0 to 0.225 V, typ, clamps not added: 23.3 ohm
|   GND clamp passes 1 mA (typ) near -0.43 V on its own axis
|   rising waveform, R_fixture 50.000, V_fixture 0.0: 20-80 % time 735ps typ, 1.28ns min, 307ps max; typ from 0 V to 0.896 V
|   rising waveform, R_fixture 50.000, V_fixture 1.500: 20-80 % time 368ps typ, 376ps min, 353ps max; typ from 0.526 V to 1.5 V
|   falling waveform, R_fixture 50.000, V_fixture 1.500: 20-80 % time 1.16ns typ, 2.2ns min, 484ps max; typ from 1.5 V to 0.526 V
|   falling waveform, R_fixture 50.000, V_fixture 0.0: 20-80 % time 382ps typ, 420ps min, 353ps max; typ from 0.896 V to 0 V
[Pulldown]
|Voltage   I(typ)   I(min)   I(max)
-1.5V     -38.2mA    -21.99mA   -59.93mA
-856mV    -38.2mA    -21.99mA   -59.93mA
-580mV    -33.29mA   -21.45mA   -51.12mA
-396mV    -24.09mA   -14.99mA   -38.38mA
156mV     8.127mA    4.623mA    13.97mA
340mV     15.07mA    8.487mA    25.9mA
524mV     19.32mA    10.78mA    33.03mA
938mV     22.73mA    12.61mA    38.32mA
1.858V    24.73mA    13.98mA    41.25mA
2.18V     29.26mA    18.55mA    45.57mA
2.548V    43.53mA    28.67mA    67.14mA
3V        67.09mA    44.94mA    103.3mA
[Pullup]
|Voltage   I(typ)   I(min)   I(max)
-1.5V     119.7mA    78.81mA    199.5mA
-1.37V    109.5mA    74.34mA    180.9mA
-1.232V   97.52mA    67.57mA    160.2mA
-588mV    40.36mA    28.31mA    66.08mA
-404mV    25.36mA    17.82mA    42.1mA
-174mV    9.761mA    6.692mA    16.69mA
10mV      -505.5uA   -338.4uA   -886.9uA
148mV     -6.75mA    -4.487mA   -11.97mA
332mV     -12.99mA   -8.529mA   -23.46mA
562mV     -17.55mA   -11.28mA   -32.68mA
838mV     -19.2mA    -12.1mA    -37.04mA
3V        -22.36mA   -13.9mA    -44.21mA
[GND_clamp]
|Voltage   I(typ)   I(min)   I(max)
-1.5V     -1.124A    -960.6mA   -1.411A
-1.097V   -411.6mA   -430.5mA   -393mA
-1.066V   -360.7mA   -392.1mA   -323mA
-1.035V   -311mA     -354.2mA   -256.8mA
-973mV    -216.9mA   -280.8mA   -144.3mA
-942mV    -173.5mA   -245.5mA   -105.7mA
-849mV    -71.09mA   -147.7mA   -64.66mA
-787mV    -39.21mA   -92.09mA   -53.75mA
-694mV    -22.05mA   -31.84mA   -35.55mA
-570mV    -8.285mA   -4.678mA   -14.06mA
-353mV    -178.3uA   -91.12uA   -279.1uA
3V        108.1uA    41.24uA    254.4uA
[POWER_clamp]
|Voltage   I(typ)   I(min)   I(max)
-1.5V     2.264uA    1.09uA     5.325uA
-1.383V   1.543uA    646.9nA    3.832uA
-1.29V    1.045uA    348.8nA    2.802uA
-1.197V   619.1nA    96.02nA    1.914uA
-1.104V   264.3nA    -108.5nA   1.168uA
-1.042V   67.89nA    -217.5nA   747.1nA
-1.011V   -18.17nA   -263.5nA   559.8nA
-918mV    -227nA     -366.2nA   89.65nA
-856mV    -323.9nA   -403.7nA   -147.4nA
-763mV    -403.1nA   -415.8nA   -387.4nA
-670mV    -411.5nA   -415.8nA   -486.7nA
1.5V      -411.5nA   -415.8nA   -489.1nA
[Ramp]
| variable   typ   min   max
dV/dt_r   0.538/0.738n   0.362/1.282n   0.734/0.305n
dV/dt_f   0.584/1.160n   0.369/2.194n   0.754/0.488n
R_load = 50.000
[Rising Waveform]
R_fixture= 50.000
V_fixture= 0.0
V_fixture_min= 0.0
V_fixture_max= 0.0
|time   V(typ)   V(min)   V(max)
0s        2.856nV    35.01nV    1.357nV
1.063ns   -116.5uV   3.047uV    -4.761mV
1.171ns   -964.6uV   3.047uV    144.8mV
1.548ns   -19.49mV   99uV       1.021V
2.058ns   -9.103mV   -527.3uV   1.199V
3.081ns   697.6mV    -6.202mV   1.222V
3.991ns   861.7mV    2.509mV    1.223V
5.454ns   892.1mV    429.7mV    1.223V
6.703ns   895.2mV    563.9mV    1.224V
20ns      896mV      602.8mV    1.224V
[Rising Waveform]
R_fixture= 50.000
V_fixture= 1.500
V_fixture_min= 1.430
V_fixture_max= 1.580
|time   V(typ)   V(min)   V(max)
0s        525.6mV    813.6mV    321.6mV
714ps     525.6mV    813.6mV    326mV
1.009ns   525.3mV    813.6mV    1.162V
1.377ns   551.1mV    813.5mV    1.541V
1.585ns   1.051V     813mV      1.564V
1.828ns   1.306V     813.6mV    1.572V
2.31ns    1.439V     793.3mV    1.576V
2.875ns   1.49V      1.281V     1.577V
3.716ns   1.497V     1.397V     1.578V
20ns      1.499V     1.429V     1.578V
[Falling Waveform]
R_fixture= 50.000
V_fixture= 1.500
V_fixture_min= 1.430
V_fixture_max= 1.580
|time   V(typ)   V(min)   V(max)
0s        1.499V     1.429V     1.578V
843ps     1.499V     1.429V     1.647V
1.139ns   1.499V     1.429V     1.564V
1.818ns   1.524V     1.429V     571.2mV
2.509ns   1.411V     1.428V     345.1mV
3.648ns   788.5mV    1.432V     322.9mV
5.191ns   552.7mV    1.282V     321.6mV
6.49ns    530mV      1.028V     321.6mV
8.323ns   525.8mV    869.5mV    321.6mV
20ns      525.5mV    813.6mV    321.6mV
[Falling Waveform]
R_fixture= 50.000
V_fixture= 0.0
V_fixture_min= 0.0
V_fixture_max= 0.0
|time   V(typ)   V(min)   V(max)
0s        896mV      602.8mV    1.224V
755ps     896mV      602.8mV    1.221V
1.044ns   896mV      602.8mV    398.6mV
1.437ns   896.5mV    602.8mV    38.68mV
1.587ns   613.5mV    602.8mV    15.48mV
1.96ns    161.4mV    603.3mV    4.198mV
2.858ns   10.81mV    444mV      448.9uV
3.288ns   3.948mV    106.3mV    130.8uV
4.106ns   948.7uV    18.2mV     31.85uV
20ns      6.343nV    95.14nV    -12.17nV
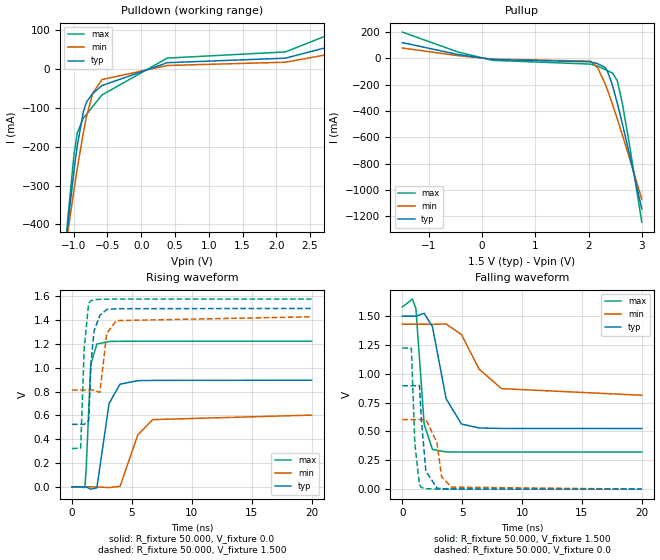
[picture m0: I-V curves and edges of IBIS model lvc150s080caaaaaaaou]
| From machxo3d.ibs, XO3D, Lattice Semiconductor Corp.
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|   Model lvc150s080caaaaaaaou
[Model] lvc150s080caaaaaaaou
Model_type Output
Polarity   Non-Inverting
Enable   Active-High
Vmeas =  0.750V
Cref =  0.0F
Rref =  1.000M
Vref =  0.0V
C_comp   4.200pF   3.800pF   7.500pF
[Temperature Range]   25.000   0.105k   -40.000
[Voltage Range]   1.500V   1.430V   1.580V
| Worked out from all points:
|   slope of the pulldown table from 0 to 0.225 V, typ, clamps not added: 20.3 ohm
|   slope of the pullup table from 0 to 0.225 V, typ, clamps not added: 23.3 ohm
|   rising waveform, R_fixture 50.000, V_fixture 0.0: 20-80 % time 740ps typ, 1.28ns min, 308ps max; typ from 0 V to 0.896 V
|   rising waveform, R_fixture 50.000, V_fixture 1.500: 20-80 % time 366ps typ, 376ps min, 350ps max; typ from 0.526 V to 1.5 V
|   falling waveform, R_fixture 50.000, V_fixture 1.500: 20-80 % time 1.16ns typ, 2.19ns min, 485ps max; typ from 1.5 V to 0.526 V
|   falling waveform, R_fixture 50.000, V_fixture 0.0: 20-80 % time 381ps typ, 419ps min, 351ps max; typ from 0.896 V to 0 V
[Pulldown]
|Voltage   I(typ)   I(min)   I(max)
-1.5V     -1.126A    -962mA     -1.414A
-1.132V   -475.8mA   -477.5mA   -486mA
-1.086V   -400.2mA   -420.1mA   -383.6mA
-994mV    -259.6mA   -309.7mA   -218mA
-948mV    -198.5mA   -257.5mA   -165.4mA
-856mV    -109.3mA   -162.8mA   -125.9mA
-810mV    -84.9mA    -122.5mA   -116.7mA
-718mV    -62.92mA   -62.31mA   -96.54mA
-580mV    -42.48mA   -26.92mA   -66.67mA
386mV     16.44mA    9.226mA    28.28mA
2.134V    28.02mA    17.62mA    44.16mA
3V        67.2mA     44.98mA    103.6mA
[Pullup]
|Voltage   I(typ)   I(min)   I(max)
-1.5V     119.8mA    78.85mA    199.8mA
-450mV    28.97mA    20.4mA     48.03mA
194mV     -8.431mA   -5.618mA   -14.96mA
2.034V    -26.45mA   -21.08mA   -43.74mA
2.172V    -40.49mA   -72.02mA   -59.15mA
2.31V     -69.17mA   -192.2mA   -84.85mA
2.356V    -98.39mA   -241.2mA   -94.02mA
2.448V    -203.4mA   -347.4mA   -111.1mA
2.54V     -340.9mA   -460.5mA   -169.2mA
2.632V    -492.3mA   -577.9mA   -335.8mA
2.77V     -731.7mA   -759.3mA   -659.4mA
3V        -1.146A    -1.07A     -1.246A
[Ramp]
| variable   typ   min   max
dV/dt_r   0.538/0.737n   0.362/1.281n   0.734/0.304n
dV/dt_f   0.584/1.159n   0.369/2.198n   0.754/0.487n
R_load = 50.000
[Rising Waveform]
R_fixture= 50.000
V_fixture= 0.0
V_fixture_min= 0.0
V_fixture_max= 0.0
|time   V(typ)   V(min)   V(max)
0s        2.83nV     35.12nV    1.331nV
1.063ns   -117.7uV   2.79uV     -4.803mV
1.171ns   -890.6uV   2.79uV     144.9mV
1.552ns   -19.47mV   99.89uV    1.027V
2.067ns   -8.219mV   -529.4uV   1.2V
3.088ns   701.5mV    -6.121mV   1.222V
4ns       862.8mV    3.342mV    1.223V
5.483ns   892.2mV    436.1mV    1.224V
6.726ns   894.7mV    565.1mV    1.224V
20ns      896mV      602.8mV    1.224V
[Rising Waveform]
R_fixture= 50.000
V_fixture= 1.500
V_fixture_min= 1.430
V_fixture_max= 1.580
|time   V(typ)   V(min)   V(max)
0s        525.6mV    813.6mV    321.6mV
714ps     525.6mV    813.6mV    326mV
1.009ns   525.3mV    813.6mV    1.164V
1.379ns   553.5mV    813.5mV    1.542V
1.585ns   1.051V     813mV      1.565V
1.835ns   1.311V     813.6mV    1.572V
2.317ns   1.442V     792.9mV    1.576V
2.895ns   1.49V      1.291V     1.577V
3.699ns   1.497V     1.397V     1.578V
20ns      1.499V     1.429V     1.578V
[Falling Waveform]
R_fixture= 50.000
V_fixture= 1.500
V_fixture_min= 1.430
V_fixture_max= 1.580
|time   V(typ)   V(min)   V(max)
0s        1.499V     1.429V     1.578V
843ps     1.499V     1.429V     1.647V
1.135ns   1.499V     1.429V     1.566V
1.826ns   1.523V     1.429V     562.2mV
2.516ns   1.408V     1.428V     344.4mV
3.661ns   783.3mV    1.431V     322.8mV
4.943ns   564.2mV    1.339V     321.7mV
6.405ns   530.4mV    1.041V     321.6mV
8.286ns   525.9mV    871mV      321.6mV
20ns      525.5mV    813.6mV    321.6mV
[Falling Waveform]
R_fixture= 50.000
V_fixture= 0.0
V_fixture_min= 0.0
V_fixture_max= 0.0
|time   V(typ)   V(min)   V(max)
0s        896mV      602.8mV    1.224V
755ps     896mV      602.8mV    1.221V
1.048ns   896.1mV    602.8mV    391.8mV
1.433ns   897.9mV    602.8mV    39.02mV
1.592ns   601.3mV    602.8mV    14.98mV
1.965ns   157.6mV    603.3mV    4.127mV
2.892ns   9.499mV    403.1mV    422.7uV
3.28ns    4.003mV    108.4mV    196.7uV
4.1ns     958.7uV    17.65mV    27.39uV
20ns      49.71nV    92.63nV    10.17nV
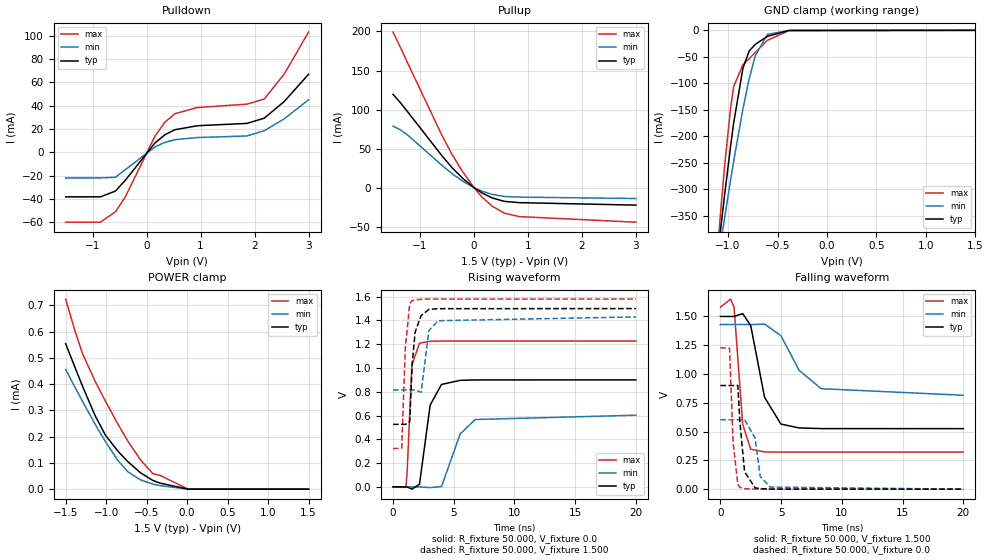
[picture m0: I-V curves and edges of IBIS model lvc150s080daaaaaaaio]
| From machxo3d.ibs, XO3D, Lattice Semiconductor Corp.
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|   Model lvc150s080daaaaaaaio
[Model] lvc150s080daaaaaaaio
Model_type I/O
Polarity   Non-Inverting
Enable   Active-Low
Vinl =  0.375V
Vinh =  1.125V
Vmeas =  0.750V
Cref =  0.0F
Rref =  1.000M
Vref =  0.0V
C_comp   4.200pF   3.800pF   7.500pF
[Temperature Range]   25.000   0.105k   -40.000
[Voltage Range]   1.500V   1.430V   1.580V
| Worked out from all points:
|   slope of the pulldown table from 0 to 0.225 V, typ, clamps not added: 20.4 ohm
|   slope of the pullup table from 0 to 0.225 V, typ, clamps not added: 23.3 ohm
|   GND clamp passes 1 mA (typ) near -0.43 V on its own axis
|   rising waveform, R_fixture 50.000, V_fixture 0.0: 20-80 % time 746ps typ, 1.28ns min, 308ps max; typ from 0 V to 0.9 V
|   rising waveform, R_fixture 50.000, V_fixture 1.500: 20-80 % time 370ps typ, 374ps min, 352ps max; typ from 0.526 V to 1.5 V
|   falling waveform, R_fixture 50.000, V_fixture 1.500: 20-80 % time 1.17ns typ, 2.18ns min, 491ps max; typ from 1.5 V to 0.526 V
|   falling waveform, R_fixture 50.000, V_fixture 0.0: 20-80 % time 390ps typ, 419ps min, 361ps max; typ from 0.9 V to 0 V
[Pulldown]
|Voltage   I(typ)   I(min)   I(max)
-1.5V     -38.2mA    -21.99mA   -59.93mA
-856mV    -38.2mA    -21.99mA   -59.93mA
-580mV    -33.29mA   -21.45mA   -51.12mA
-396mV    -24.09mA   -14.99mA   -38.38mA
156mV     8.127mA    4.623mA    13.97mA
340mV     15.07mA    8.487mA    25.9mA
524mV     19.32mA    10.78mA    33.03mA
938mV     22.73mA    12.61mA    38.32mA
1.858V    24.74mA    13.98mA    41.25mA
2.18V     29.24mA    18.53mA    45.59mA
2.548V    43.44mA    28.61mA    67.01mA
3V        66.87mA    45mA       103mA
[Pullup]
|Voltage   I(typ)   I(min)   I(max)
-1.5V     119.5mA    78.9mA     199.2mA
-1.37V    109.3mA    74.35mA    180.6mA
-1.232V   97.37mA    67.54mA    160mA
-588mV    40.35mA    28.3mA     66.08mA
-404mV    25.36mA    17.82mA    42.19mA
-220mV    12.63mA    8.708mA    21.47mA
10mV      -505.5uA   -338.4uA   -886.9uA
148mV     -6.75mA    -4.487mA   -11.97mA
332mV     -12.99mA   -8.529mA   -23.46mA
562mV     -17.55mA   -11.28mA   -32.68mA
838mV     -19.2mA    -12.1mA    -37.04mA
3V        -22.36mA   -13.9mA    -44.21mA
[GND_clamp]
|Voltage   I(typ)   I(min)   I(max)
-1.5V     -1.124A    -960.6mA   -1.411A
-1.097V   -411.6mA   -430.5mA   -393mA
-1.066V   -360.7mA   -392.1mA   -323mA
-1.035V   -311mA     -354.2mA   -256.8mA
-973mV    -216.9mA   -280.8mA   -144.3mA
-942mV    -173.5mA   -245.5mA   -105.7mA
-849mV    -71.09mA   -147.7mA   -64.66mA
-787mV    -39.21mA   -92.09mA   -53.75mA
-725mV    -26.45mA   -48.04mA   -41.65mA
-601mV    -11.21mA   -7.588mA   -18.81mA
-384mV    -319.8uA   -151.2uA   -484.4uA
1.5V      -41.68nA   0A         -8.283uA
[POWER_clamp]
|Voltage   I(typ)   I(min)   I(max)
-1.5V     553.8uA    455.7uA    723.9uA
-1.383V   462uA      386.8uA    600.3uA
-1.29V    390.6uA    333.2uA    514.8uA
-1.135V   279.1uA    247uA      410.2uA
-1.011V   206.7uA    182uA      336.5uA
-856mV    145uA      109.7uA    248.3uA
-732mV    104.8uA    66.29uA    183.2uA
-577mV    62.52uA    35.6uA     111.7uA
-422mV    33.03uA    19.13uA    58.98uA
-329mV    22.6uA     13.31uA    51.73uA
12mV      0A         0A         0A
1.5V      0A         0A         0A
[Ramp]
| variable   typ   min   max
dV/dt_r   0.540/0.741n   0.362/1.282n   0.736/0.307n
dV/dt_f   0.585/1.172n   0.369/2.182n   0.755/0.492n
R_load = 50.000
[Rising Waveform]
R_fixture= 50.000
V_fixture= 0.0
V_fixture_min= 0.0
V_fixture_max= 0.0
|time   V(typ)   V(min)   V(max)
0s        2.856nV    35.01nV    1.357nV
1.063ns   -116.6uV   3.475uV    -4.761mV
1.171ns   -964.5uV   3.475uV    144.8mV
1.548ns   -19.49mV   98.99uV    1.021V
2.178ns   20.85mV    -936.8uV   1.209V
3.058ns   687.8mV    -6.525mV   1.225V
3.991ns   861.7mV    2.509mV    1.227V
5.529ns   896.3mV    444.8mV    1.227V
6.764ns   899.4mV    566.5mV    1.227V
20ns      899.9mV    602.8mV    1.227V
[Rising Waveform]
R_fixture= 50.000
V_fixture= 1.500
V_fixture_min= 1.430
V_fixture_max= 1.580
|time   V(typ)   V(min)   V(max)
0s        525.6mV    815.7mV    321.6mV
714ps     525.6mV    815.7mV    326mV
1.009ns   525.3mV    815.7mV    1.162V
1.375ns   548.7mV    815.5mV    1.542V
1.577ns   1.035V     815.1mV    1.566V
1.824ns   1.304V     815.6mV    1.574V
2.314ns   1.441V     795mV      1.578V
2.953ns   1.493V     1.316V     1.58V
3.719ns   1.499V     1.398V     1.58V
20ns      1.5V       1.43V      1.58V
[Falling Waveform]
R_fixture= 50.000
V_fixture= 1.500
V_fixture_min= 1.430
V_fixture_max= 1.580
|time   V(typ)   V(min)   V(max)
0s        1.5V       1.43V      1.58V
844ps     1.5V       1.43V      1.651V
1.127ns   1.5V       1.43V      1.58V
1.835ns   1.525V     1.43V      564.2mV
2.501ns   1.42V      1.429V     347.1mV
3.638ns   797.4mV    1.434V     323.2mV
4.985ns   565.4mV    1.333V     321.7mV
6.483ns   531.9mV    1.032V     321.6mV
8.305ns   526.1mV    872.4mV    321.6mV
20ns      525.5mV    815.7mV    321.6mV
[Falling Waveform]
R_fixture= 50.000
V_fixture= 0.0
V_fixture_min= 0.0
V_fixture_max= 0.0
|time   V(typ)   V(min)   V(max)
0s        899.9mV    602.8mV    1.227V
755ps     900mV      602.8mV    1.225V
1.043ns   900mV      602.8mV    411.1mV
1.437ns   900.4mV    602.8mV    41.89mV
1.598ns   591.9mV    602.8mV    15.53mV
1.991ns   151.7mV    603.6mV    4.095mV
2.858ns   11.24mV    444mV      394.6uV
3.276ns   4.207mV    110.2mV    177.9uV
4.106ns   1.008mV    18.2mV     52.69uV
20ns      4.687nV    95.14nV    -11.67nV
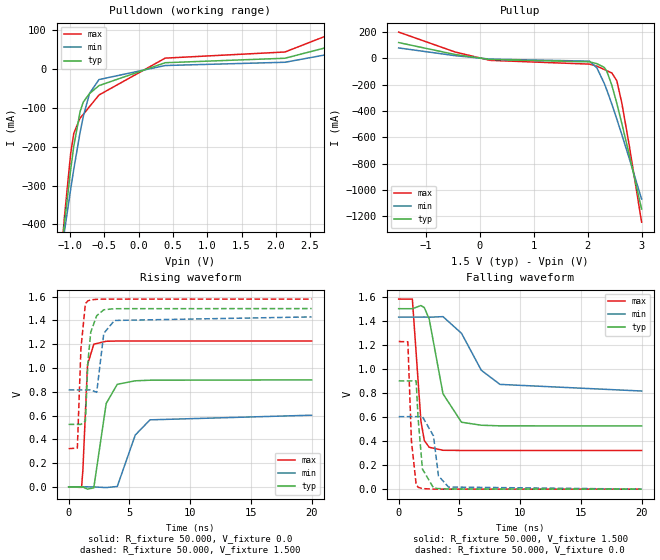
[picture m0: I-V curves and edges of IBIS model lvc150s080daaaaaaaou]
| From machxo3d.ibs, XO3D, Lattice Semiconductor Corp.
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|   Model lvc150s080daaaaaaaou
[Model] lvc150s080daaaaaaaou
Model_type Output
Polarity   Non-Inverting
Enable   Active-High
Vmeas =  0.750V
Cref =  0.0F
Rref =  1.000M
Vref =  0.0V
C_comp   4.200pF   3.800pF   7.500pF
[Temperature Range]   25.000   0.105k   -40.000
[Voltage Range]   1.500V   1.430V   1.580V
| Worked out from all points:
|   slope of the pulldown table from 0 to 0.225 V, typ, clamps not added: 20.3 ohm
|   slope of the pullup table from 0 to 0.225 V, typ, clamps not added: 23.3 ohm
|   rising waveform, R_fixture 50.000, V_fixture 0.0: 20-80 % time 743ps typ, 1.28ns min, 306ps max; typ from 0 V to 0.9 V
|   rising waveform, R_fixture 50.000, V_fixture 1.500: 20-80 % time 369ps typ, 374ps min, 351ps max; typ from 0.526 V to 1.5 V
|   falling waveform, R_fixture 50.000, V_fixture 1.500: 20-80 % time 1.17ns typ, 2.17ns min, 489ps max; typ from 1.5 V to 0.526 V
|   falling waveform, R_fixture 50.000, V_fixture 0.0: 20-80 % time 386ps typ, 418ps min, 359ps max; typ from 0.9 V to 0 V
[Pulldown]
|Voltage   I(typ)   I(min)   I(max)
-1.5V     -1.126A    -962mA     -1.414A
-1.132V   -475.8mA   -477.5mA   -486mA
-1.086V   -400.2mA   -420.1mA   -383.6mA
-994mV    -259.6mA   -309.7mA   -218mA
-948mV    -198.5mA   -257.5mA   -165.4mA
-856mV    -109.3mA   -162.8mA   -125.9mA
-810mV    -84.9mA    -122.5mA   -116.7mA
-718mV    -62.92mA   -62.31mA   -96.54mA
-580mV    -42.48mA   -26.92mA   -66.67mA
386mV     16.44mA    9.226mA    28.28mA
2.134V    27.98mA    17.63mA    44.05mA
3V        67.42mA    45.5mA     103.7mA
[Pullup]
|Voltage   I(typ)   I(min)   I(max)
-1.5V     120.1mA    79.35mA    199.9mA
-450mV    28.91mA    20.38mA    47.88mA
194mV     -8.541mA   -5.66mA    -15.21mA
2.034V    -26.45mA   -21.08mA   -43.74mA
2.172V    -40.49mA   -72.02mA   -59.15mA
2.31V     -69.17mA   -192.2mA   -84.85mA
2.356V    -98.39mA   -241.2mA   -94.02mA
2.448V    -203.4mA   -347.4mA   -111.1mA
2.54V     -340.9mA   -460.5mA   -169.2mA
2.632V    -492.3mA   -577.9mA   -335.8mA
2.77V     -731.7mA   -759.3mA   -659.4mA
3V        -1.146A    -1.07A     -1.246A
[Ramp]
| variable   typ   min   max
dV/dt_r   0.540/0.740n   0.362/1.281n   0.736/0.306n
dV/dt_f   0.585/1.169n   0.369/2.190n   0.755/0.491n
R_load = 50.000
[Rising Waveform]
R_fixture= 50.000
V_fixture= 0.0
V_fixture_min= 0.0
V_fixture_max= 0.0
|time   V(typ)   V(min)   V(max)
0s        2.83nV     35.12nV    1.331nV
1.063ns   -117.7uV   2.784uV    -4.803mV
1.171ns   -890.6uV   2.784uV    144.9mV
1.552ns   -19.47mV   99.88uV    1.027V
2.067ns   -8.219mV   -529.4uV   1.2V
3.088ns   701.5mV    -6.121mV   1.225V
4ns       862.8mV    3.342mV    1.227V
5.483ns   892.2mV    436.1mV    1.227V
6.696ns   897.3mV    563.8mV    1.227V
20ns      899.9mV    602.8mV    1.227V
[Rising Waveform]
R_fixture= 50.000
V_fixture= 1.500
V_fixture_min= 1.430
V_fixture_max= 1.580
|time   V(typ)   V(min)   V(max)
0s        525.6mV    815.7mV    321.6mV
714ps     525.6mV    815.7mV    326mV
1.009ns   525.3mV    815.7mV    1.164V
1.379ns   553.5mV    815.5mV    1.542V
1.585ns   1.051V     815.1mV    1.565V
1.818ns   1.302V     815.6mV    1.573V
2.308ns   1.44V      795.2mV    1.578V
2.893ns   1.49V      1.292V     1.58V
3.771ns   1.499V     1.4V       1.58V
20ns      1.5V       1.43V      1.58V
[Falling Waveform]
R_fixture= 50.000
V_fixture= 1.500
V_fixture_min= 1.430
V_fixture_max= 1.580
|time   V(typ)   V(min)   V(max)
0s        1.5V       1.43V      1.58V
1.127ns   1.5V       1.43V      1.58V
1.831ns   1.526V     1.43V      567.1mV
2.111ns   1.509V     1.431V     404mV
2.513ns   1.414V     1.429V     348mV
3.65ns    792.5mV    1.434V     323.2mV
5.175ns   556.3mV    1.295V     321.7mV
6.806ns   531.4mV    987.9mV    321.6mV
8.34ns    526.3mV    870.8mV    321.6mV
20ns      525.5mV    815.7mV    321.6mV
[Falling Waveform]
R_fixture= 50.000
V_fixture= 0.0
V_fixture_min= 0.0
V_fixture_max= 0.0
|time   V(typ)   V(min)   V(max)
0s        899.9mV    602.8mV    1.227V
755ps     900mV      602.8mV    1.225V
1.049ns   900mV      602.8mV    401.6mV
1.437ns   900.5mV    602.8mV    40.87mV
1.599ns   589.5mV    602.8mV    15.71mV
1.954ns   167.5mV    603.2mV    4.65mV
2.865ns   11.23mV    442.6mV    517.5uV
3.274ns   4.728mV    110.5mV    166.8uV
4.1ns     1.408mV    17.65mV    47.49uV
20ns      52.71nV    92.63nV    3.978nV
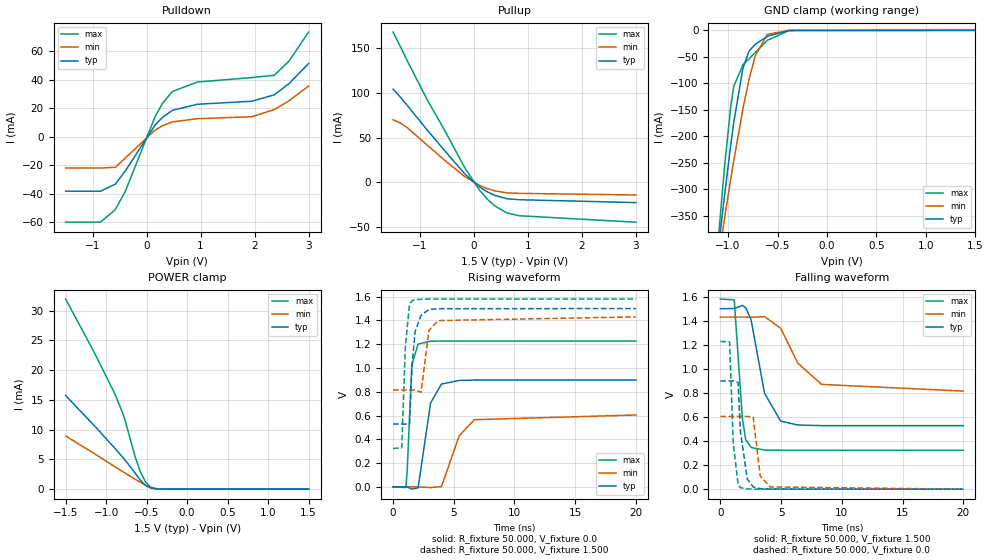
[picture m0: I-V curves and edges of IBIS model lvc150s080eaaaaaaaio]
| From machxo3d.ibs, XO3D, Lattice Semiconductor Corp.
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|   Model lvc150s080eaaaaaaaio
[Model] lvc150s080eaaaaaaaio
Model_type I/O
Polarity   Non-Inverting
Enable   Active-Low
Vinl =  0.375V
Vinh =  1.125V
Vmeas =  0.750V
Cref =  0.0F
Rref =  1.000M
Vref =  0.0V
C_comp   4.200pF   3.800pF   7.500pF
[Temperature Range]   25.000   0.105k   -40.000
[Voltage Range]   1.500V   1.430V   1.580V
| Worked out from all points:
|   slope of the pulldown table from 0 to 0.225 V, typ, clamps not added: 20.4 ohm
|   slope of the pullup table from 0 to 0.225 V, typ, clamps not added: 23.3 ohm
|   GND clamp passes 1 mA (typ) near -0.44 V on its own axis
|   POWER clamp passes 1 mA (typ) near -0.55 V on its own axis
|   rising waveform, R_fixture 50.000, V_fixture 0.0: 20-80 % time 733ps typ, 1.28ns min, 306ps max; typ from 0 V to 0.899 V
|   rising waveform, R_fixture 50.000, V_fixture 1.500: 20-80 % time 363ps typ, 375ps min, 348ps max; typ from 0.528 V to 1.5 V
|   falling waveform, R_fixture 50.000, V_fixture 1.500: 20-80 % time 1.16ns typ, 2.2ns min, 488ps max; typ from 1.5 V to 0.528 V
|   falling waveform, R_fixture 50.000, V_fixture 0.0: 20-80 % time 387ps typ, 422ps min, 361ps max; typ from 0.899 V to 0 V
[Pulldown]
|Voltage   I(typ)   I(min)   I(max)
-1.5V     -38.2mA    -21.99mA   -59.93mA
-856mV    -38.2mA    -21.99mA   -59.93mA
-580mV    -33.29mA   -21.45mA   -51.12mA
-396mV    -24.09mA   -14.99mA   -38.38mA
156mV     8.127mA    4.623mA    13.97mA
294mV     13.59mA    7.677mA    23.37mA
478mV     18.49mA    10.34mA    31.68mA
938mV     22.73mA    12.61mA    38.32mA
1.95V     24.84mA    13.99mA    41.43mA
2.364V    29.33mA    18.99mA    43.04mA
2.64V     37.26mA    25.2mA     53.1mA
3V        51.31mA    35.43mA    73.31mA
[Pullup]
|Voltage   I(typ)   I(min)   I(max)
-1.5V     103.9mA    69.84mA    167.5mA
-1.37V    95.54mA    66.43mA    152.1mA
-1.232V   85.55mA    60.83mA    135mA
-864mV    58.19mA    41.47mA    91.8mA
-542mV    35.44mA    24.73mA    57.94mA
-174mV    9.761mA    6.692mA    16.69mA
102mV     -4.819mA   -3.211mA   -8.515mA
240mV     -10.16mA   -6.718mA   -18.18mA
378mV     -14.18mA   -9.28mA    -25.75mA
608mV     -18.05mA   -11.55mA   -33.86mA
838mV     -19.2mA    -12.1mA    -37.04mA
3V        -22.36mA   -13.9mA    -44.21mA
[GND_clamp]
|Voltage   I(typ)   I(min)   I(max)
-1.5V     -1.124A    -960.6mA   -1.411A
-1.097V   -411.6mA   -430.5mA   -392.9mA
-1.066V   -360.7mA   -392.1mA   -323mA
-1.035V   -311mA     -354.2mA   -256.7mA
-973mV    -216.8mA   -280.8mA   -144.2mA
-942mV    -173.4mA   -245.5mA   -105.6mA
-849mV    -71.05mA   -147.7mA   -64.59mA
-787mV    -39.16mA   -92.07mA   -53.68mA
-725mV    -26.4mA    -48.02mA   -41.58mA
-601mV    -11.15mA   -7.544mA   -18.72mA
-384mV    -236.4uA   -103.3uA   -351.1uA
1.5V      0A         0A         0A
[POWER_clamp]
|Voltage   I(typ)   I(min)   I(max)
-1.5V     15.72mA    8.929mA    31.93mA
-1.135V   10.5mA     5.879mA    22.65mA
-887mV    6.787mA    3.722mA    15.85mA
-794mV    5.333mA    2.928mA    12.72mA
-763mV    4.831mA    2.666mA    11.38mA
-639mV    2.654mA    1.642mA    5.303mA
-577mV    1.493mA    1.154mA    2.909mA
-515mV    627.3uA    700.9uA    1.235mA
-453mV    200.7uA    325.5uA    363.9uA
-391mV    56.19uA    99.29uA    82.51uA
-298mV    7.73uA     11.12uA    7.668uA
1.5V      0A         0A         4.131nA
[Ramp]
| variable   typ   min   max
dV/dt_r   0.540/0.734n   0.363/1.282n   0.736/0.304n
dV/dt_f   0.583/1.160n   0.369/2.194n   0.754/0.489n
R_load = 50.000
[Rising Waveform]
R_fixture= 50.000
V_fixture= 0.0
V_fixture_min= 0.0
V_fixture_max= 0.0
|time   V(typ)   V(min)   V(max)
0s        2.959nV    35.35nV    1.474nV
1.062ns   -115.1uV   3.547uV    -5.7mV
1.172ns   -965.2uV   3.547uV    146.7mV
1.547ns   -19.55mV   99.15uV    1.024V
2.063ns   -8.774mV   -558.2uV   1.202V
3.095ns   706.3mV    -6.027mV   1.225V
3.99ns    865.1mV    2.39mV     1.227V
5.449ns   895.3mV    429.7mV    1.227V
6.699ns   898.4mV    565.2mV    1.227V
20ns      899.2mV    604.4mV    1.227V
[Rising Waveform]
R_fixture= 50.000
V_fixture= 1.500
V_fixture_min= 1.430
V_fixture_max= 1.580
|time   V(typ)   V(min)   V(max)
0s        527.9mV    815.2mV    323.4mV
714ps     527.9mV    815.2mV    327.9mV
1.014ns   527.5mV    815.2mV    1.176V
1.357ns   533.8mV    815.1mV    1.539V
1.581ns   1.047V     814.6mV    1.567V
1.826ns   1.309V     815.2mV    1.574V
2.308ns   1.443V     794.8mV    1.578V
2.958ns   1.493V     1.318V     1.58V
3.74ns    1.499V     1.399V     1.58V
20ns      1.5V       1.43V      1.58V
[Falling Waveform]
R_fixture= 50.000
V_fixture= 1.500
V_fixture_min= 1.430
V_fixture_max= 1.580
|time   V(typ)   V(min)   V(max)
0s        1.5V       1.43V      1.58V
1.14ns    1.501V     1.43V      1.573V
1.812ns   1.528V     1.43V      585.3mV
2.086ns   1.509V     1.43V      411.2mV
2.526ns   1.408V     1.429V     346.4mV
3.637ns   796.7mV    1.434V     324.7mV
4.963ns   565.6mV    1.337V     323.5mV
6.38ns    533mV      1.047V     323.4mV
8.332ns   528.1mV    870.7mV    323.4mV
20ns      527.7mV    815.2mV    323.4mV
[Falling Waveform]
R_fixture= 50.000
V_fixture= 0.0
V_fixture_min= 0.0
V_fixture_max= 0.0
|time   V(typ)   V(min)   V(max)
0s        899.2mV    604.4mV    1.227V
755ps     899.2mV    604.4mV    1.225V
1.058ns   899.3mV    604.4mV    388mV
1.459ns   886.3mV    604.4mV    34.42mV
1.65ns    480.4mV    604.4mV    12.25mV
2.215ns   84.34mV    604.8mV    2.018mV
2.7ns     18.62mV    598.6mV    604.9uV
3.286ns   4.012mV    108mV      132.4uV
4.104ns   991.2uV    18.59mV    32.53uV
20ns      7.195nV    97.15nV    -7.209nV
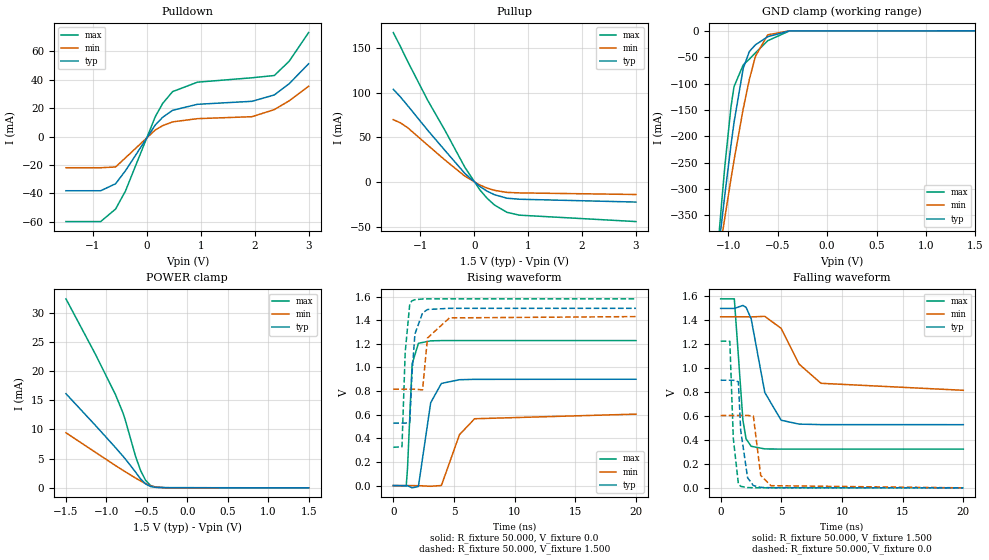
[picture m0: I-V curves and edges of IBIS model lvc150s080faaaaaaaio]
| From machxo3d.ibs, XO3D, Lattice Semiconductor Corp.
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|   Model lvc150s080faaaaaaaio
[Model] lvc150s080faaaaaaaio
Model_type I/O
Polarity   Non-Inverting
Enable   Active-Low
Vinl =  0.375V
Vinh =  1.125V
Vmeas =  0.750V
Cref =  0.0F
Rref =  1.000M
Vref =  0.0V
C_comp   4.200pF   3.800pF   7.500pF
[Temperature Range]   25.000   0.105k   -40.000
[Voltage Range]   1.500V   1.430V   1.580V
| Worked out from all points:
|   slope of the pulldown table from 0 to 0.225 V, typ, clamps not added: 20.4 ohm
|   slope of the pullup table from 0 to 0.225 V, typ, clamps not added: 23.3 ohm
|   GND clamp passes 1 mA (typ) near -0.44 V on its own axis
|   POWER clamp passes 1 mA (typ) near -0.54 V on its own axis
|   rising waveform, R_fixture 50.000, V_fixture 0.0: 20-80 % time 732ps typ, 1.28ns min, 304ps max; typ from 0 V to 0.9 V
|   rising waveform, R_fixture 50.000, V_fixture 1.500: 20-80 % time 364ps typ, 376ps min, 346ps max; typ from 0.529 V to 1.5 V
|   falling waveform, R_fixture 50.000, V_fixture 1.500: 20-80 % time 1.16ns typ, 2.18ns min, 490ps max; typ from 1.5 V to 0.528 V
|   falling waveform, R_fixture 50.000, V_fixture 0.0: 20-80 % time 388ps typ, 424ps min, 361ps max; typ from 0.9 V to 0 V
[Pulldown]
|Voltage   I(typ)   I(min)   I(max)
-1.5V     -38.2mA    -21.99mA   -59.93mA
-856mV    -38.2mA    -21.99mA   -59.93mA
-580mV    -33.29mA   -21.45mA   -51.12mA
-396mV    -24.09mA   -14.99mA   -38.38mA
156mV     8.127mA    4.623mA    13.97mA
294mV     13.59mA    7.677mA    23.37mA
478mV     18.49mA    10.34mA    31.68mA
938mV     22.73mA    12.61mA    38.32mA
1.95V     24.84mA    13.99mA    41.43mA
2.364V    29.33mA    18.99mA    43.02mA
2.64V     37.25mA    25.2mA     53.09mA
3V        51.3mA     35.44mA    73.29mA
[Pullup]
|Voltage   I(typ)   I(min)   I(max)
-1.5V     103.9mA    69.92mA    167.5mA
-1.37V    95.55mA    66.47mA    152.1mA
-1.232V   85.56mA    60.85mA    135mA
-864mV    58.19mA    41.48mA    91.79mA
-542mV    35.44mA    24.73mA    57.94mA
-174mV    9.761mA    6.692mA    16.69mA
102mV     -4.819mA   -3.211mA   -8.515mA
240mV     -10.16mA   -6.718mA   -18.18mA
378mV     -14.18mA   -9.28mA    -25.75mA
608mV     -18.05mA   -11.55mA   -33.86mA
838mV     -19.2mA    -12.1mA    -37.04mA
3V        -22.36mA   -13.9mA    -44.21mA
[GND_clamp]
|Voltage   I(typ)   I(min)   I(max)
-1.5V     -1.124A    -960.6mA   -1.411A
-1.097V   -411.6mA   -430.5mA   -392.9mA
-1.066V   -360.7mA   -392.1mA   -323mA
-1.035V   -311mA     -354.2mA   -256.7mA
-973mV    -216.8mA   -280.8mA   -144.3mA
-942mV    -173.5mA   -245.5mA   -105.7mA
-849mV    -71.06mA   -147.7mA   -64.61mA
-787mV    -39.17mA   -92.07mA   -53.7mA
-725mV    -26.41mA   -48.02mA   -41.6mA
-601mV    -11.16mA   -7.552mA   -18.74mA
-384mV    -258.6uA   -114.9uA   -396.2uA
1.5V      -41.68nA   0A         -8.283uA
[POWER_clamp]
|Voltage   I(typ)   I(min)   I(max)
-1.5V     16.13mA    9.435mA    32.38mA
-1.135V   10.69mA    6.084mA    22.87mA
-887mV    6.888mA    3.813mA    15.95mA
-794mV    5.406mA    2.992mA    12.8mA
-763mV    4.897mA    2.724mA    11.46mA
-639mV    2.697mA    1.677mA    5.367mA
-577mV    1.529mA    1.181mA    2.962mA
-515mV    656.7uA    722.8uA    1.279mA
-453mV    227.4uA    343.3uA    403.8uA
-391mV    80.76uA    114.4uA    122.7uA
-267mV    21.1uA     15.5uA     34.42uA
1.5V      0A         0A         0A
[Ramp]
| variable   typ   min   max
dV/dt_r   0.540/0.732n   0.363/1.282n   0.736/0.304n
dV/dt_f   0.583/1.164n   0.369/2.182n   0.754/0.490n
R_load = 50.000
[Rising Waveform]
R_fixture= 50.000
V_fixture= 0.0
V_fixture_min= 0.0
V_fixture_max= 0.0
|time   V(typ)   V(min)   V(max)
0s        304.8uV    218.6uV    443.3uV
1.063ns   191.7uV    222.2uV    -3.144mV
1.169ns   -552.7uV   222.2uV    142.4mV
1.552ns   -18.88mV   318.7uV    1.031V
2.07ns    -6.937mV   -340.7uV   1.204V
3.08ns    701.1mV    -5.696mV   1.225V
3.963ns   864.5mV    786.3uV    1.227V
5.452ns   896mV      430.8mV    1.227V
6.702ns   899.1mV    565.8mV    1.227V
20ns      899.9mV    604.9mV    1.227V
[Rising Waveform]
R_fixture= 50.000
V_fixture= 1.500
V_fixture_min= 1.430
V_fixture_max= 1.580
|time   V(typ)   V(min)   V(max)
0s        528.5mV    815.7mV    324.1mV
714ps     528.5mV    815.7mV    328.7mV
980ps     528.2mV    815.7mV    1.129V
1.359ns   536.1mV    815.5mV    1.54V
1.528ns   929.7mV    815.5mV    1.563V
1.782ns   1.283V     815.4mV    1.573V
2.41ns    1.461V     810.1mV    1.579V
2.818ns   1.49V      1.249V     1.58V
4.629ns   1.5V       1.419V     1.58V
20ns      1.5V       1.43V      1.58V
[Falling Waveform]
R_fixture= 50.000
V_fixture= 1.500
V_fixture_min= 1.430
V_fixture_max= 1.580
|time   V(typ)   V(min)   V(max)
0s        1.5V       1.43V      1.58V
1.127ns   1.5V       1.43V      1.58V
1.835ns   1.525V     1.43V      564.2mV
2.095ns   1.509V     1.43V      409.6mV
2.515ns   1.413V     1.429V     347.9mV
3.638ns   797.4mV    1.434V     325.5mV
4.985ns   565.4mV    1.333V     324.2mV
6.462ns   533.1mV    1.035V     324.1mV
8.266ns   528.8mV    874.1mV    324.1mV
20ns      528.3mV    815.7mV    324.1mV
[Falling Waveform]
R_fixture= 50.000
V_fixture= 0.0
V_fixture_min= 0.0
V_fixture_max= 0.0
|time   V(typ)   V(min)   V(max)
0s        899.9mV    604.9mV    1.227V
755ps     900mV      605mV      1.225V
1.043ns   900mV      605mV      411.1mV
1.459ns   887.1mV    605mV      35.42mV
1.649ns   483.4mV    605mV      12.89mV
2.219ns   84.75mV    605.4mV    2.555mV
2.697ns   19.56mV    600.4mV    1.102mV
3.299ns   4.233mV    104.5mV    600.1uV
4.136ns   1.238mV    18.34mV    486.1uV
20ns      304.7uV    218.7uV    443.3uV
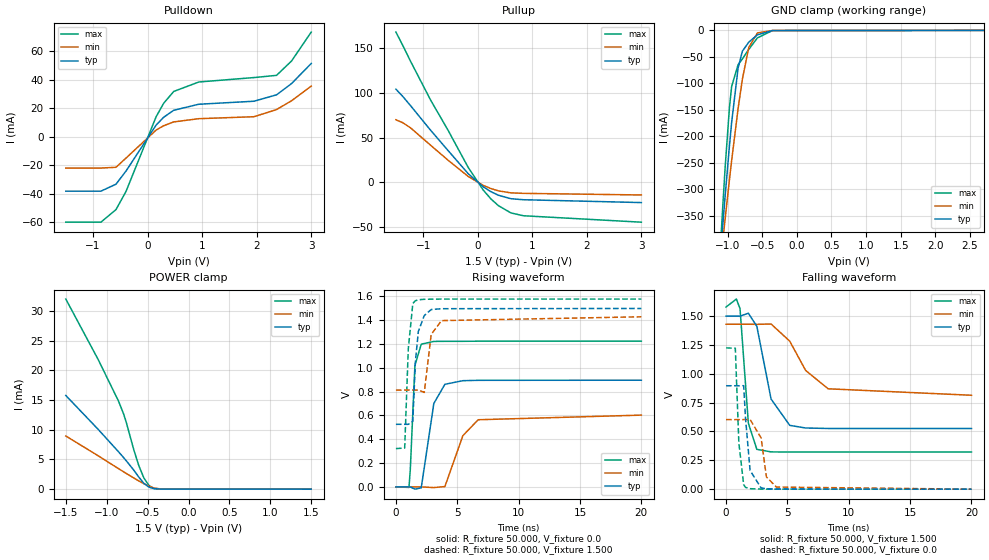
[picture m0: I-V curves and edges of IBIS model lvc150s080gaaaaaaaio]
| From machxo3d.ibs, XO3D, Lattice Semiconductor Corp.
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|   Model lvc150s080gaaaaaaaio
[Model] lvc150s080gaaaaaaaio
Model_type I/O
Polarity   Non-Inverting
Enable   Active-Low
Vinl =  0.375V
Vinh =  1.125V
Vmeas =  0.750V
Cref =  0.0F
Rref =  1.000M
Vref =  0.0V
C_comp   4.200pF   3.800pF   7.500pF
[Temperature Range]   25.000   0.105k   -40.000
[Voltage Range]   1.500V   1.430V   1.580V
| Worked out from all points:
|   slope of the pulldown table from 0 to 0.225 V, typ, clamps not added: 20.4 ohm
|   slope of the pullup table from 0 to 0.225 V, typ, clamps not added: 23.3 ohm
|   GND clamp passes 1 mA (typ) near -0.43 V on its own axis
|   POWER clamp passes 1 mA (typ) near -0.55 V on its own axis
|   rising waveform, R_fixture 50.000, V_fixture 0.0: 20-80 % time 734ps typ, 1.28ns min, 307ps max; typ from 0 V to 0.896 V
|   rising waveform, R_fixture 50.000, V_fixture 1.500: 20-80 % time 368ps typ, 376ps min, 353ps max; typ from 0.526 V to 1.5 V
|   falling waveform, R_fixture 50.000, V_fixture 1.500: 20-80 % time 1.16ns typ, 2.2ns min, 484ps max; typ from 1.5 V to 0.526 V
|   falling waveform, R_fixture 50.000, V_fixture 0.0: 20-80 % time 382ps typ, 420ps min, 353ps max; typ from 0.896 V to 0 V
[Pulldown]
|Voltage   I(typ)   I(min)   I(max)
-1.5V     -38.2mA    -21.99mA   -59.93mA
-856mV    -38.2mA    -21.99mA   -59.93mA
-580mV    -33.29mA   -21.45mA   -51.12mA
-396mV    -24.09mA   -14.99mA   -38.38mA
156mV     8.127mA    4.623mA    13.97mA
294mV     13.59mA    7.677mA    23.37mA
478mV     18.49mA    10.34mA    31.68mA
938mV     22.73mA    12.61mA    38.32mA
1.95V     24.84mA    13.99mA    41.43mA
2.364V    29.33mA    18.99mA    42.98mA
2.64V     37.25mA    25.2mA     53.08mA
3V        51.3mA     35.43mA    73.3mA
[Pullup]
|Voltage   I(typ)   I(min)   I(max)
-1.5V     103.9mA    69.85mA    167.5mA
-1.37V    95.55mA    66.44mA    152.1mA
-1.232V   85.56mA    60.84mA    135mA
-864mV    58.19mA    41.47mA    91.79mA
-542mV    35.45mA    24.73mA    57.94mA
-174mV    9.761mA    6.692mA    16.69mA
102mV     -4.819mA   -3.211mA   -8.515mA
240mV     -10.16mA   -6.718mA   -18.18mA
378mV     -14.18mA   -9.28mA    -25.75mA
608mV     -18.05mA   -11.55mA   -33.86mA
838mV     -19.2mA    -12.1mA    -37.04mA
3V        -22.36mA   -13.9mA    -44.21mA
[GND_clamp]
|Voltage   I(typ)   I(min)   I(max)
-1.5V     -1.124A    -960.6mA   -1.411A
-1.097V   -411.6mA   -430.5mA   -393mA
-1.066V   -360.7mA   -392.1mA   -323mA
-1.035V   -311mA     -354.2mA   -256.8mA
-973mV    -216.9mA   -280.8mA   -144.3mA
-942mV    -173.5mA   -245.5mA   -105.7mA
-849mV    -71.09mA   -147.7mA   -64.66mA
-787mV    -39.21mA   -92.09mA   -53.75mA
-694mV    -22.05mA   -31.84mA   -35.55mA
-570mV    -8.285mA   -4.678mA   -14.06mA
-353mV    -178.3uA   -91.12uA   -279.1uA
3V        108.1uA    41.24uA    254.4uA
[POWER_clamp]
|Voltage   I(typ)   I(min)   I(max)
-1.5V     15.78mA    8.958mA    32.02mA
-1.104V   10.07mA    5.622mA    21.83mA
-856mV    6.305mA    3.46mA     14.84mA
-794mV    5.324mA    2.93mA     12.69mA
-763mV    4.82mA     2.667mA    11.36mA
-670mV    3.216mA    1.891mA    6.697mA
-608mV    2.042mA    1.391mA    3.973mA
-546mV    979.4uA    916.1uA    1.9mA
-484mV    340.1uA    494.4uA    627.5uA
-422mV    90.48uA    185.7uA    125.7uA
-329mV    10.53uA    21.57uA    6.907uA
1.5V      0A         0A         -3.95nA
[Ramp]
| variable   typ   min   max
dV/dt_r   0.538/0.738n   0.362/1.282n   0.734/0.305n
dV/dt_f   0.584/1.160n   0.369/2.194n   0.754/0.488n
R_load = 50.000
[Rising Waveform]
R_fixture= 50.000
V_fixture= 0.0
V_fixture_min= 0.0
V_fixture_max= 0.0
|time   V(typ)   V(min)   V(max)
0s        2.856nV    35.01nV    1.357nV
1.063ns   -116.5uV   3.047uV    -4.761mV
1.171ns   -964.6uV   3.047uV    144.8mV
1.548ns   -19.49mV   98.99uV    1.021V
2.063ns   -8.633mV   -527.3uV   1.199V
3.089ns   701mV      -6.202mV   1.222V
3.991ns   861.7mV    2.509mV    1.223V
5.454ns   892.1mV    429.7mV    1.223V
6.703ns   895.2mV    563.9mV    1.224V
20ns      896mV      602.8mV    1.224V
[Rising Waveform]
R_fixture= 50.000
V_fixture= 1.500
V_fixture_min= 1.430
V_fixture_max= 1.580
|time   V(typ)   V(min)   V(max)
0s        525.6mV    813.6mV    321.6mV
714ps     525.6mV    813.6mV    326mV
1.009ns   525.3mV    813.6mV    1.162V
1.377ns   551.1mV    813.5mV    1.541V
1.585ns   1.051V     813mV      1.564V
1.828ns   1.306V     813.6mV    1.572V
2.31ns    1.439V     793.3mV    1.576V
2.875ns   1.49V      1.281V     1.577V
3.716ns   1.497V     1.397V     1.578V
20ns      1.499V     1.429V     1.578V
[Falling Waveform]
R_fixture= 50.000
V_fixture= 1.500
V_fixture_min= 1.430
V_fixture_max= 1.580
|time   V(typ)   V(min)   V(max)
0s        1.499V     1.429V     1.578V
843ps     1.499V     1.429V     1.647V
1.139ns   1.499V     1.429V     1.564V
1.818ns   1.524V     1.429V     571.2mV
2.509ns   1.411V     1.428V     345.1mV
3.67ns    780.5mV    1.431V     322.9mV
5.191ns   552.7mV    1.282V     321.6mV
6.49ns    530mV      1.028V     321.6mV
8.323ns   525.8mV    869.5mV    321.6mV
20ns      525.5mV    813.6mV    321.6mV
[Falling Waveform]
R_fixture= 50.000
V_fixture= 0.0
V_fixture_min= 0.0
V_fixture_max= 0.0
|time   V(typ)   V(min)   V(max)
0s        896mV      602.8mV    1.224V
755ps     896mV      602.8mV    1.221V
1.044ns   896mV      602.8mV    398.6mV
1.437ns   896.5mV    602.8mV    38.68mV
1.587ns   613.5mV    602.8mV    15.48mV
1.96ns    161.4mV    603.3mV    4.198mV
2.858ns   10.81mV    444mV      448.9uV
3.288ns   3.948mV    106.3mV    130.8uV
4.106ns   948.7uV    18.2mV     31.85uV
20ns      6.343nV    95.14nV    -12.17nV
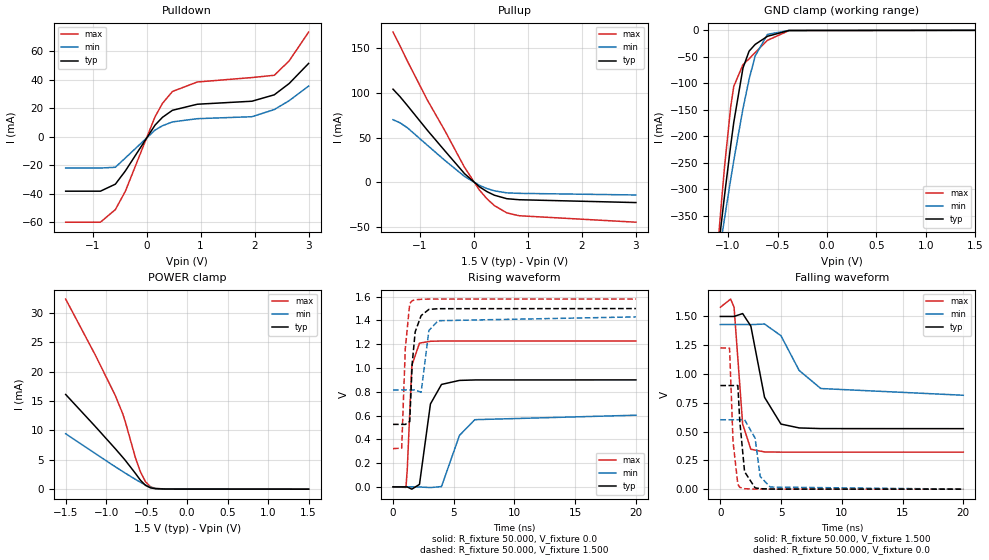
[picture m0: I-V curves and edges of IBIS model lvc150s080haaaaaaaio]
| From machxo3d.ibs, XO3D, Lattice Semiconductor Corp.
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|   Model lvc150s080haaaaaaaio
[Model] lvc150s080haaaaaaaio
Model_type I/O
Polarity   Non-Inverting
Enable   Active-Low
Vinl =  0.375V
Vinh =  1.125V
Vmeas =  0.750V
Cref =  0.0F
Rref =  1.000M
Vref =  0.0V
C_comp   4.200pF   3.800pF   7.500pF
[Temperature Range]   25.000   0.105k   -40.000
[Voltage Range]   1.500V   1.430V   1.580V
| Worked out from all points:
|   slope of the pulldown table from 0 to 0.225 V, typ, clamps not added: 20.4 ohm
|   slope of the pullup table from 0 to 0.225 V, typ, clamps not added: 23.3 ohm
|   GND clamp passes 1 mA (typ) near -0.43 V on its own axis
|   POWER clamp passes 1 mA (typ) near -0.54 V on its own axis
|   rising waveform, R_fixture 50.000, V_fixture 0.0: 20-80 % time 743ps typ, 1.28ns min, 308ps max; typ from 0 V to 0.9 V
|   rising waveform, R_fixture 50.000, V_fixture 1.500: 20-80 % time 370ps typ, 374ps min, 354ps max; typ from 0.526 V to 1.5 V
|   falling waveform, R_fixture 50.000, V_fixture 1.500: 20-80 % time 1.17ns typ, 2.19ns min, 490ps max; typ from 1.5 V to 0.526 V
|   falling waveform, R_fixture 50.000, V_fixture 0.0: 20-80 % time 390ps typ, 419ps min, 361ps max; typ from 0.9 V to 0 V
[Pulldown]
|Voltage   I(typ)   I(min)   I(max)
-1.5V     -38.2mA    -21.99mA   -59.93mA
-856mV    -38.2mA    -21.99mA   -59.93mA
-580mV    -33.29mA   -21.45mA   -51.12mA
-396mV    -24.09mA   -14.99mA   -38.38mA
156mV     8.127mA    4.623mA    13.97mA
294mV     13.59mA    7.677mA    23.37mA
478mV     18.49mA    10.34mA    31.68mA
938mV     22.73mA    12.61mA    38.32mA
1.95V     24.84mA    13.99mA    41.43mA
2.364V    29.33mA    18.99mA    43.02mA
2.64V     37.25mA    25.2mA     53.09mA
3V        51.3mA     35.44mA    73.29mA
[Pullup]
|Voltage   I(typ)   I(min)   I(max)
-1.5V     103.9mA    69.92mA    167.5mA
-1.37V    95.55mA    66.47mA    152.1mA
-1.232V   85.56mA    60.85mA    135mA
-864mV    58.19mA    41.48mA    91.79mA
-542mV    35.44mA    24.73mA    57.94mA
-174mV    9.761mA    6.692mA    16.69mA
102mV     -4.819mA   -3.211mA   -8.515mA
240mV     -10.16mA   -6.718mA   -18.18mA
378mV     -14.18mA   -9.28mA    -25.75mA
608mV     -18.05mA   -11.55mA   -33.86mA
838mV     -19.2mA    -12.1mA    -37.04mA
3V        -22.36mA   -13.9mA    -44.21mA
[GND_clamp]
|Voltage   I(typ)   I(min)   I(max)
-1.5V     -1.124A    -960.6mA   -1.411A
-1.097V   -411.6mA   -430.5mA   -393mA
-1.066V   -360.7mA   -392.1mA   -323mA
-1.035V   -311mA     -354.2mA   -256.8mA
-973mV    -216.9mA   -280.8mA   -144.3mA
-942mV    -173.5mA   -245.5mA   -105.7mA
-849mV    -71.09mA   -147.7mA   -64.66mA
-787mV    -39.21mA   -92.09mA   -53.75mA
-725mV    -26.45mA   -48.04mA   -41.65mA
-601mV    -11.21mA   -7.588mA   -18.81mA
-384mV    -319.8uA   -151.2uA   -484.4uA
1.5V      -41.68nA   0A         -8.283uA
[POWER_clamp]
|Voltage   I(typ)   I(min)   I(max)
-1.5V     16.13mA    9.435mA    32.38mA
-1.135V   10.69mA    6.084mA    22.87mA
-887mV    6.888mA    3.813mA    15.95mA
-794mV    5.406mA    2.992mA    12.8mA
-763mV    4.897mA    2.724mA    11.46mA
-639mV    2.697mA    1.677mA    5.367mA
-577mV    1.529mA    1.181mA    2.962mA
-515mV    656.7uA    722.8uA    1.279mA
-453mV    227.4uA    343.3uA    403.8uA
-391mV    80.76uA    114.4uA    122.7uA
-267mV    21.1uA     15.5uA     34.42uA
1.5V      0A         0A         0A
[Ramp]
| variable   typ   min   max
dV/dt_r   0.540/0.741n   0.362/1.282n   0.736/0.307n
dV/dt_f   0.585/1.172n   0.369/2.182n   0.755/0.492n
R_load = 50.000
[Rising Waveform]
R_fixture= 50.000
V_fixture= 0.0
V_fixture_min= 0.0
V_fixture_max= 0.0
|time   V(typ)   V(min)   V(max)
0s        2.856nV    35.01nV    1.357nV
1.063ns   -116.5uV   3.476uV    -4.761mV
1.171ns   -964.5uV   3.476uV    144.8mV
1.548ns   -19.49mV   98.99uV    1.021V
2.178ns   20.85mV    -936.8uV   1.209V
3.081ns   697.6mV    -6.202mV   1.225V
3.991ns   861.7mV    2.509mV    1.227V
5.469ns   895.6mV    432.8mV    1.227V
6.733ns   899.4mV    565.2mV    1.227V
20ns      899.9mV    602.8mV    1.227V
[Rising Waveform]
R_fixture= 50.000
V_fixture= 1.500
V_fixture_min= 1.430
V_fixture_max= 1.580
|time   V(typ)   V(min)   V(max)
0s        525.6mV    815.7mV    321.6mV
714ps     525.6mV    815.7mV    326mV
1.009ns   525.3mV    815.7mV    1.162V
1.375ns   548.7mV    815.5mV    1.542V
1.577ns   1.035V     815.1mV    1.566V
1.824ns   1.304V     815.6mV    1.574V
2.314ns   1.441V     795.1mV    1.578V
2.953ns   1.493V     1.316V     1.58V
3.719ns   1.499V     1.398V     1.58V
20ns      1.5V       1.43V      1.58V
[Falling Waveform]
R_fixture= 50.000
V_fixture= 1.500
V_fixture_min= 1.430
V_fixture_max= 1.580
|time   V(typ)   V(min)   V(max)
0s        1.5V       1.43V      1.58V
844ps     1.5V       1.43V      1.651V
1.127ns   1.5V       1.43V      1.58V
1.834ns   1.525V     1.43V      565.2mV
2.508ns   1.416V     1.429V     346.7mV
3.638ns   797.4mV    1.434V     323.2mV
4.985ns   565.4mV    1.333V     321.7mV
6.487ns   531.9mV    1.031V     321.6mV
8.266ns   526.1mV    874.1mV    321.6mV
20ns      525.5mV    815.7mV    321.6mV
[Falling Waveform]
R_fixture= 50.000
V_fixture= 0.0
V_fixture_min= 0.0
V_fixture_max= 0.0
|time   V(typ)   V(min)   V(max)
0s        899.9mV    602.8mV    1.227V
755ps     900mV      602.8mV    1.225V
1.043ns   900mV      602.8mV    411.1mV
1.437ns   900.4mV    602.8mV    41.89mV
1.598ns   591.9mV    602.8mV    15.53mV
1.991ns   151.7mV    603.6mV    4.095mV
2.858ns   11.24mV    444mV      394.6uV
3.276ns   4.207mV    110.2mV    177.9uV
4.106ns   1.009mV    18.2mV     52.69uV
20ns      4.688nV    95.14nV    -11.67nV
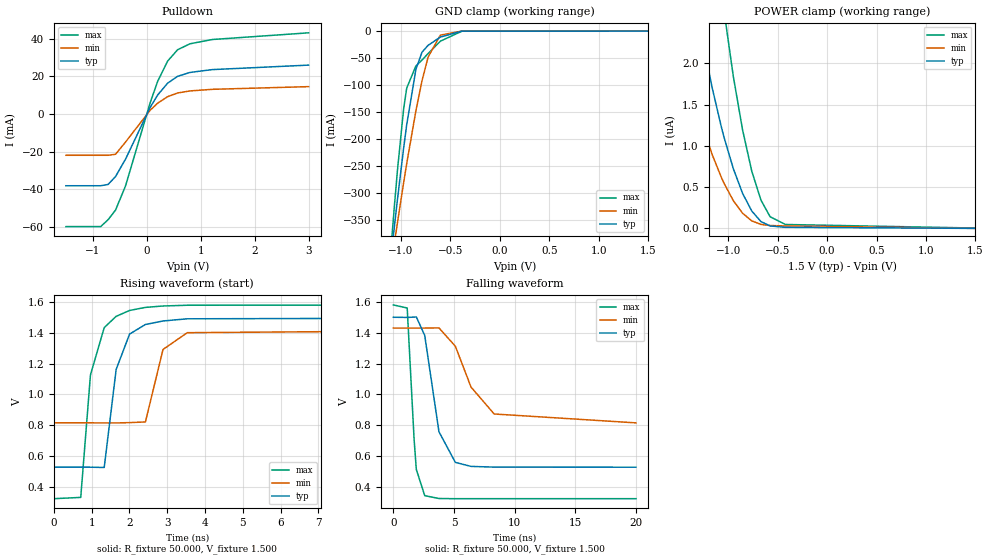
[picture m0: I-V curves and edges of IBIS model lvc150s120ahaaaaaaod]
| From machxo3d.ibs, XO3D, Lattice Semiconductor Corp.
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|   Model lvc150s120ahaaaaaaod
[Model] lvc150s120ahaaaaaaod
Model_type I/O_open_drain
Polarity   Non-Inverting
Enable   Active-Low
Vinl =  0.375V
Vinh =  1.125V
Vmeas =  0.750V
Cref =  0.0F
Rref = 10.00k
Vref = 1.50V
C_comp   4.200pF   3.800pF   7.500pF
[Temperature Range]   25.000   0.105k   -40.000
[Voltage Range]   1.500V   1.430V   1.580V
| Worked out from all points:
|   slope of the pulldown table from 0 to 0.225 V, typ, clamps not added: 20.4 ohm
|   GND clamp passes 1 mA (typ) near -0.44 V on its own axis
|   rising waveform, R_fixture 50.000, V_fixture 1.500: 20-80 % time 351ps typ, 377ps min, 351ps max; typ from 0.528 V to 1.5 V
|   falling waveform, R_fixture 50.000, V_fixture 1.500: 20-80 % time 1.16ns typ, 2.19ns min, 492ps max; typ from 1.5 V to 0.528 V
[Pulldown]
|Voltage   I(typ)   I(min)   I(max)
-1.5V     -38.2mA    -21.99mA   -59.93mA
-856mV    -38.2mA    -21.99mA   -59.93mA
-718mV    -37.5mA    -21.99mA   -56.26mA
-580mV    -33.29mA   -21.45mA   -51.12mA
-396mV    -24.09mA   -14.99mA   -38.38mA
64mV      3.591mA    2.051mA    6.169mA
202mV     10.12mA    5.747mA    17.41mA
386mV     16.37mA    9.198mA    28.13mA
570mV     20.01mA    11.14mA    34.13mA
800mV     22.07mA    12.24mA    37.32mA
1.214V    23.58mA    13.09mA    39.59mA
3V        25.97mA    14.52mA    43.15mA
[GND_clamp]
|Voltage   I(typ)   I(min)   I(max)
-1.5V     -1.124A    -960.6mA   -1.411A
-1.097V   -411.6mA   -430.5mA   -392.9mA
-1.066V   -360.7mA   -392.1mA   -323mA
-1.035V   -311mA     -354.2mA   -256.8mA
-973mV    -216.9mA   -280.8mA   -144.3mA
-942mV    -173.5mA   -245.5mA   -105.7mA
-849mV    -71.07mA   -147.7mA   -64.62mA
-787mV    -39.18mA   -92.07mA   -53.7mA
-725mV    -26.42mA   -48.02mA   -41.6mA
-601mV    -11.16mA   -7.547mA   -18.74mA
-384mV    -237.5uA   -103.4uA   -356uA
1.5V      0A         0A         0A
[POWER_clamp]
|Voltage   I(typ)   I(min)   I(max)
-1.5V     4.017uA    2.297uA    8.486uA
-1.321V   2.676uA    1.475uA    5.815uA
-1.166V   1.719uA    902.9nA    3.892uA
-1.073V   1.242uA    625.4nA    2.92uA
-1.042V   1.099uA    544.2nA    2.626uA
-949mV    723.1nA    335.9nA    1.84uA
-856mV    425.6nA    184nA      1.196uA
-763mV    211.1nA    90.96nA    695.6nA
-670mV    83.04nA    48.44nA    343.1nA
-577mV    29.38nA    34.64nA    141nA
-422mV    12.83nA    29.52nA    47.28nA
1.5V      0A         0A         4.136nA
[Ramp]
| variable   typ   min   max
dV/dt_r   0.583/0.347n   0.369/0.373n   0.754/0.349n
dV/dt_f   0.583/1.161n   0.369/2.203n   0.754/0.492n
R_load = 50.000
[Rising Waveform]
R_fixture= 50.000
V_fixture= 1.500
V_fixture_min= 1.430
V_fixture_max= 1.580
|time   V(typ)   V(min)   V(max)
0s        527.9mV    815.2mV    323.4mV
712ps     527.9mV    815.2mV    331.8mV
969ps     527.7mV    815.2mV    1.126V
1.333ns   525.8mV    815.1mV    1.433V
1.649ns   1.162V     814.6mV    1.506V
2.004ns   1.391V     816.8mV    1.544V
2.423ns   1.453V     821.1mV    1.564V
2.888ns   1.476V     1.291V     1.573V
3.53ns    1.49V      1.4V       1.578V
20ns      1.5V       1.43V      1.58V
[Falling Waveform]
R_fixture= 50.000
V_fixture= 1.500
V_fixture_min= 1.430
V_fixture_max= 1.580
|time   V(typ)   V(min)   V(max)
0s        1.5V       1.43V      1.58V
1.145ns   1.499V     1.43V      1.56V
1.717ns   1.501V     1.43V      704.3mV
1.897ns   1.502V     1.43V      513mV
2.59ns    1.382V     1.43V      343.1mV
3.763ns   757.4mV    1.431V     324.6mV
5.115ns   558.8mV    1.312V     323.4mV
6.407ns   532.8mV    1.047V     323.4mV
8.314ns   528.2mV    872.7mV    323.4mV
20ns      527.6mV    815.2mV    323.4mV
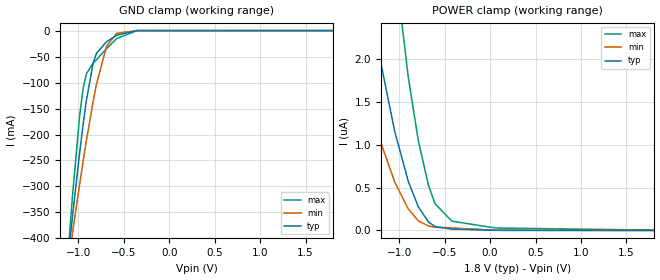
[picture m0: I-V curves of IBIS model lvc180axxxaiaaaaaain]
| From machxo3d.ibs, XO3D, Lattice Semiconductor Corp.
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|   Model lvc180axxxaiaaaaaain
[Model] lvc180axxxaiaaaaaain
Model_type Input
Polarity   Non-Inverting
Enable   Active-High
Vinl =  0.630V
Vinh =  1.170V
C_comp   4.200pF   3.800pF   7.500pF
[Temperature Range]   25.000   0.105k   -40.000
[Voltage Range]   1.800V   1.710V   1.890V
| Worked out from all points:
|   GND clamp passes 1 mA (typ) near -0.44 V on its own axis
[GND_clamp]
|Voltage   I(typ)   I(min)   I(max)
-1.8V     -1.677A    -1.372A    -2.207A
-1.097V   -411.6mA   -430.5mA   -392.9mA
-1.06V    -351mA     -384.7mA   -309.8mA
-986mV    -235.9mA   -295.9mA   -164.7mA
-949mV    -183mA     -253.4mA   -113mA
-912mV    -135mA     -212.5mA   -83.3mA
-838mV    -63.14mA   -137.2mA   -62.64mA
-801mV    -43.91mA   -103.8mA   -56.23mA
-690mV    -21.48mA   -30.06mA   -34.7mA
-579mV    -9.036mA   -5.342mA   -15.29mA
-357mV    -109.7uA   -52.3uA    -160.5uA
1.8V      0A         0A         0A
[POWER_clamp]
|Voltage   I(typ)   I(min)   I(max)
-1.8V     6.918uA    4.075uA    15.53uA
-1.641V   5.335uA    3.081uA    12.17uA
-1.382V   3.16uA     1.741uA    7.507uA
-1.197V   1.931uA    1.01uA     4.843uA
-1.049V   1.156uA    564.4nA    3.128uA
-901mV    576.3nA    251.8nA    1.796uA
-790mV    276.2nA    113.3nA    1.051uA
-679mV    99.6nA     51.84nA    530.4nA
-605mV    45.39nA    37.95nA    310.9nA
-420mV    15.43nA    30.15nA    108.3nA
61mV      1.598nA    2.498nA    28.82nA
1.8V      0A         0A         4.225nA
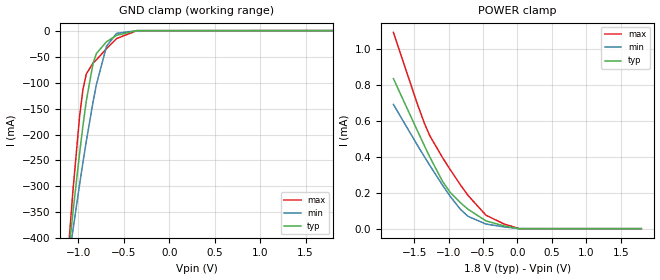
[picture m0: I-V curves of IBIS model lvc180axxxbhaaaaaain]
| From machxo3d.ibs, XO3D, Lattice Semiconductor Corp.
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|   Model lvc180axxxbhaaaaaain
[Model] lvc180axxxbhaaaaaain
Model_type Input
Polarity   Non-Inverting
Enable   Active-High
Vinl =  0.630V
Vinh =  1.170V
C_comp   4.200pF   3.800pF   7.500pF
[Temperature Range]   25.000   0.105k   -40.000
[Voltage Range]   1.800V   1.710V   1.890V
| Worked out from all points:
|   GND clamp passes 1 mA (typ) near -0.44 V on its own axis
[GND_clamp]
|Voltage   I(typ)   I(min)   I(max)
-1.8V     -1.677A    -1.372A    -2.207A
-1.097V   -411.6mA   -430.5mA   -393mA
-1.06V    -351mA     -384.7mA   -309.9mA
-986mV    -235.9mA   -295.9mA   -164.7mA
-949mV    -183mA     -253.4mA   -113mA
-912mV    -135mA     -212.5mA   -83.35mA
-838mV    -63.17mA   -137.2mA   -62.69mA
-801mV    -43.94mA   -103.8mA   -56.28mA
-690mV    -21.51mA   -30.07mA   -34.75mA
-579mV    -9.065mA   -5.356mA   -15.35mA
-357mV    -147.5uA   -72.3uA    -237.1uA
1.8V      -12.41nA   0A         -10.91uA
[POWER_clamp]
|Voltage   I(typ)   I(min)   I(max)
-1.8V     836.1uA    692.5uA    1.094mA
-1.456V   549uA      467.8uA    698.7uA
-1.345V   458uA      397.8uA    582.4uA
-1.271V   398.7uA    352uA      517.3uA
-1.086V   262.9uA    241.7uA    395.6uA
-975mV    202uA      179.8uA    328.7uA
-827mV    144.5uA    107.4uA    243.8uA
-716mV    108uA      68.49uA    184.9uA
-457mV    43.42uA    25.76uA    75.17uA
-198mV    15.77uA    10.09uA    26.67uA
24mV      0A         0A         0A
1.8V      0A         0A         0A
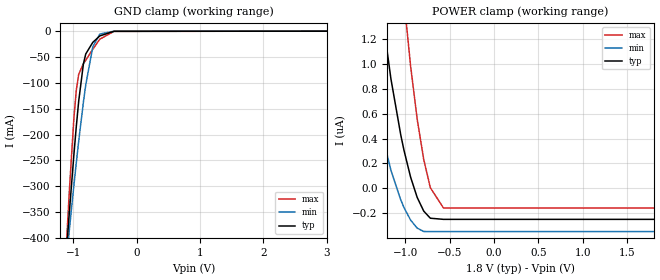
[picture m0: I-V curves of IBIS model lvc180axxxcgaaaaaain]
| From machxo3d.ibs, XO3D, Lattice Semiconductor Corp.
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|   Model lvc180axxxcgaaaaaain
[Model] lvc180axxxcgaaaaaain
Model_type Input
Polarity   Non-Inverting
Enable   Active-High
Vinl =  0.630V
Vinh =  1.170V
C_comp   4.200pF   3.800pF   7.500pF
[Temperature Range]   25.000   0.105k   -40.000
[Voltage Range]   1.800V   1.710V   1.890V
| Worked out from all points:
|   GND clamp passes 1 mA (typ) near -0.44 V on its own axis
[GND_clamp]
|Voltage   I(typ)   I(min)   I(max)
-1.8V     -1.677A    -1.372A    -2.207A
-1.097V   -411.7mA   -430.5mA   -393mA
-1.06V    -351mA     -384.7mA   -309.9mA
-986mV    -235.9mA   -295.9mA   -164.7mA
-949mV    -183mA     -253.4mA   -113.1mA
-912mV    -135mA     -212.5mA   -83.39mA
-838mV    -63.2mA    -137.2mA   -62.72mA
-801mV    -43.97mA   -103.8mA   -56.32mA
-690mV    -21.54mA   -30.09mA   -34.79mA
-579mV    -9.102mA   -5.388mA   -15.4mA
-357mV    -191.3uA   -96.81uA   -298.1uA
3.6V      109.7uA    43.11uA    257.2uA
[POWER_clamp]
|Voltage   I(typ)   I(min)   I(max)
-1.8V     5.719uA    2.93uA     14.07uA
-1.567V   3.495uA    1.631uA    8.906uA
-1.308V   1.654uA    575.3nA    4.658uA
-1.16V    879.4nA    146.2nA    2.868uA
-1.049V   429nA      -91.44nA   1.808uA
-1.012V   303.6nA    -154.2nA   1.506uA
-938mV    90.39nA    -254.1nA   980.4nA
-864mV    -72.13nA   -318nA     555.3nA
-790mV    -182.2nA   -345.2nA   230.5nA
-716mV    -238.7nA   -345.8nA   6.19nA
-568mV    -247.9nA   -345.8nA   -157nA
1.8V      -247.9nA   -345.8nA   -157nA
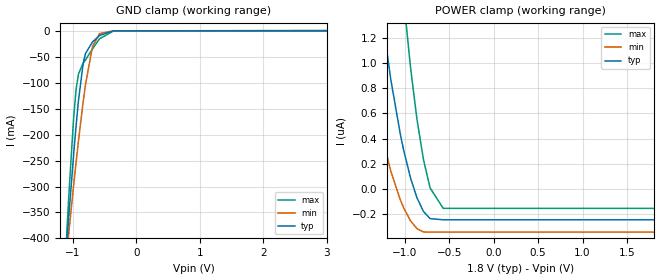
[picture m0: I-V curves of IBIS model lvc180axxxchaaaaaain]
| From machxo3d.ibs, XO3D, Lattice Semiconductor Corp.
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|   Model lvc180axxxchaaaaaain
[Model] lvc180axxxchaaaaaain
Model_type Input
Polarity   Non-Inverting
Enable   Active-High
Vinl =  0.630V
Vinh =  1.170V
C_comp   4.200pF   3.800pF   7.500pF
[Temperature Range]   25.000   0.105k   -40.000
[Voltage Range]   1.800V   1.710V   1.890V
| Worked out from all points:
|   GND clamp passes 1 mA (typ) near -0.44 V on its own axis
[GND_clamp]
|Voltage   I(typ)   I(min)   I(max)
-1.8V     -1.677A    -1.372A    -2.207A
-1.097V   -411.7mA   -430.5mA   -393mA
-1.06V    -351mA     -384.7mA   -309.9mA
-986mV    -235.9mA   -295.9mA   -164.8mA
-949mV    -183mA     -253.4mA   -113.1mA
-912mV    -135mA     -212.5mA   -83.39mA
-838mV    -63.2mA    -137.2mA   -62.73mA
-801mV    -43.97mA   -103.8mA   -56.32mA
-690mV    -21.54mA   -30.09mA   -34.79mA
-579mV    -9.102mA   -5.388mA   -15.4mA
-357mV    -191.3uA   -96.81uA   -298.1uA
3.6V      109.7uA    43.11uA    257.2uA
[POWER_clamp]
|Voltage   I(typ)   I(min)   I(max)
-1.8V     5.719uA    2.929uA    14.07uA
-1.567V   3.495uA    1.631uA    8.906uA
-1.308V   1.654uA    574.5nA    4.658uA
-1.16V    879.1nA    145.5nA    2.867uA
-1.049V   428.7nA    -92.06nA   1.807uA
-1.012V   303.4nA    -154.8nA   1.506uA
-938mV    90.14nA    -254.6nA   980.1nA
-864mV    -72.35nA   -318.5nA   555.1nA
-790mV    -182.4nA   -345.6nA   230.3nA
-716mV    -238.9nA   -346.3nA   6nA
-568mV    -248.1nA   -346.3nA   -157.2nA
1.8V      -248.1nA   -346.3nA   -157.2nA
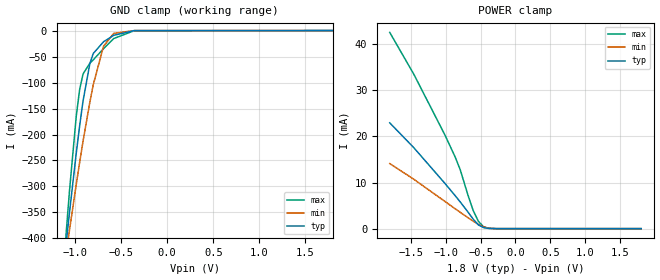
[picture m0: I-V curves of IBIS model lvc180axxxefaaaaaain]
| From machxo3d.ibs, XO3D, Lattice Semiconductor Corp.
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|   Model lvc180axxxefaaaaaain
[Model] lvc180axxxefaaaaaain
Model_type Input
Polarity   Non-Inverting
Enable   Active-High
Vinl =  0.630V
Vinh =  1.170V
C_comp   4.200pF   3.800pF   7.500pF
[Temperature Range]   25.000   0.105k   -40.000
[Voltage Range]   1.800V   1.710V   1.890V
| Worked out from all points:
|   GND clamp passes 1 mA (typ) near -0.44 V on its own axis
|   POWER clamp passes 1 mA (typ) near -0.54 V on its own axis
[GND_clamp]
|Voltage   I(typ)   I(min)   I(max)
-1.8V     -1.677A    -1.372A    -2.207A
-1.097V   -411.6mA   -430.5mA   -392.9mA
-1.06V    -351mA     -384.7mA   -309.8mA
-986mV    -235.9mA   -295.9mA   -164.7mA
-949mV    -183mA     -253.4mA   -113mA
-912mV    -135mA     -212.5mA   -83.31mA
-838mV    -63.15mA   -137.2mA   -62.65mA
-801mV    -43.92mA   -103.8mA   -56.24mA
-690mV    -21.48mA   -30.06mA   -34.71mA
-579mV    -9.039mA   -5.342mA   -15.3mA
-357mV    -110.1uA   -52.31uA   -165uA
1.8V      0A         0A         0A
[POWER_clamp]
|Voltage   I(typ)   I(min)   I(max)
-1.8V     22.96mA    14.12mA    42.58mA
-1.456V   17.58mA    10.73mA    33.53mA
-1.012V   9.862mA    5.93mA     20.39mA
-864mV    7.169mA    4.324mA    15.58mA
-790mV    5.782mA    3.533mA    12.76mA
-679mV    3.597mA    2.373mA    7.228mA
-605mV    2.06mA     1.63mA     3.944mA
-531mV    817.1uA    941.7uA    1.603mA
-457mV    219.8uA    380.4uA    401.4uA
-383mV    48.82uA    85.34uA    69.63uA
-272mV    4.681uA    6.23uA     4.313uA
1.8V      0A         0A         4.22nA
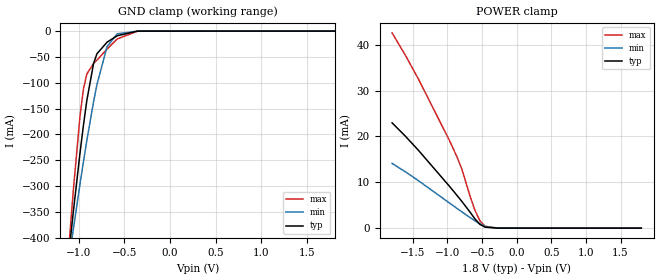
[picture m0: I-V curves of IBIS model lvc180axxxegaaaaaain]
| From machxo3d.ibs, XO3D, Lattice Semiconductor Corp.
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|   Model lvc180axxxegaaaaaain
[Model] lvc180axxxegaaaaaain
Model_type Input
Polarity   Non-Inverting
Enable   Active-High
Vinl =  0.630V
Vinh =  1.170V
C_comp   4.200pF   3.800pF   7.500pF
[Temperature Range]   25.000   0.105k   -40.000
[Voltage Range]   1.800V   1.710V   1.890V
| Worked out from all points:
|   GND clamp passes 1 mA (typ) near -0.44 V on its own axis
|   POWER clamp passes 1 mA (typ) near -0.54 V on its own axis
[GND_clamp]
|Voltage   I(typ)   I(min)   I(max)
-1.8V     -1.677A    -1.372A    -2.207A
-1.097V   -411.6mA   -430.5mA   -392.9mA
-1.06V    -351mA     -384.7mA   -309.8mA
-986mV    -235.9mA   -295.9mA   -164.7mA
-949mV    -183mA     -253.4mA   -113mA
-912mV    -135mA     -212.5mA   -83.32mA
-838mV    -63.15mA   -137.2mA   -62.66mA
-801mV    -43.92mA   -103.8mA   -56.25mA
-690mV    -21.49mA   -30.06mA   -34.72mA
-579mV    -9.043mA   -5.343mA   -15.31mA
-357mV    -110.3uA   -52.32uA   -166.5uA
1.8V      0A         0A         0A
[POWER_clamp]
|Voltage   I(typ)   I(min)   I(max)
-1.8V     22.96mA    14.12mA    42.58mA
-1.604V   19.99mA    12.25mA    37.59mA
-1.419V   16.97mA    10.35mA    32.49mA
-975mV    9.198mA    5.526mA    19.24mA
-864mV    7.172mA    4.324mA    15.59mA
-790mV    5.786mA    3.533mA    12.78mA
-679mV    3.602mA    2.373mA    7.241mA
-605mV    2.064mA    1.631mA    3.953mA
-531mV    819.3uA    942.3uA    1.607mA
-457mV    220.7uA    380.8uA    403.7uA
-272mV    4.697uA    6.247uA    4.346uA
1.8V      0A         0A         4.226nA
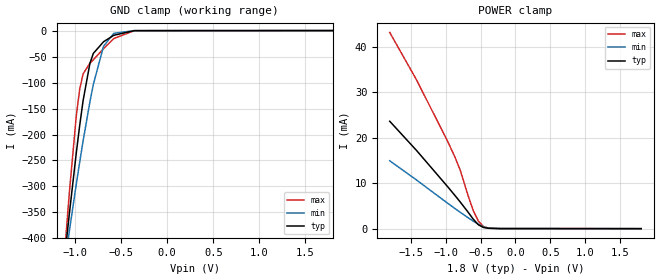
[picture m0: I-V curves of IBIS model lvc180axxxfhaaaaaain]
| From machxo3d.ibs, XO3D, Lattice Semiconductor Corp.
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|   Model lvc180axxxfhaaaaaain
[Model] lvc180axxxfhaaaaaain
Model_type Input
Polarity   Non-Inverting
Enable   Active-High
Vinl =  0.630V
Vinh =  1.170V
C_comp   4.200pF   3.800pF   7.500pF
[Temperature Range]   25.000   0.105k   -40.000
[Voltage Range]   1.800V   1.710V   1.890V
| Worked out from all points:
|   GND clamp passes 1 mA (typ) near -0.44 V on its own axis
|   POWER clamp passes 1 mA (typ) near -0.54 V on its own axis
[GND_clamp]
|Voltage   I(typ)   I(min)   I(max)
-1.8V     -1.677A    -1.372A    -2.207A
-1.097V   -411.6mA   -430.5mA   -393mA
-1.06V    -351mA     -384.7mA   -309.9mA
-986mV    -235.9mA   -295.9mA   -164.7mA
-949mV    -183mA     -253.4mA   -113mA
-912mV    -135mA     -212.5mA   -83.35mA
-838mV    -63.17mA   -137.2mA   -62.69mA
-801mV    -43.94mA   -103.8mA   -56.28mA
-690mV    -21.51mA   -30.07mA   -34.75mA
-579mV    -9.065mA   -5.356mA   -15.35mA
-357mV    -147.5uA   -72.3uA    -237.1uA
1.8V      -12.41nA   0A         -10.91uA
[POWER_clamp]
|Voltage   I(typ)   I(min)   I(max)
-1.8V     23.65mA    14.95mA    43.22mA
-1.419V   17.27mA    10.75mA    32.84mA
-975mV    9.322mA    5.649mA    19.37mA
-864mV    7.265mA    4.408mA    15.69mA
-790mV    5.86mA     3.598mA    12.87mA
-679mV    3.655mA    2.417mA    7.32mA
-605mV    2.107mA    1.665mA    4.016mA
-531mV    854uA      968.7uA    1.658mA
-457mV    251.6uA    402uA      448.6uA
-383mV    77.17uA    103.3uA    115.3uA
-235mV    19.9uA     13.46uA    32.69uA
1.8V      0A         0A         0A
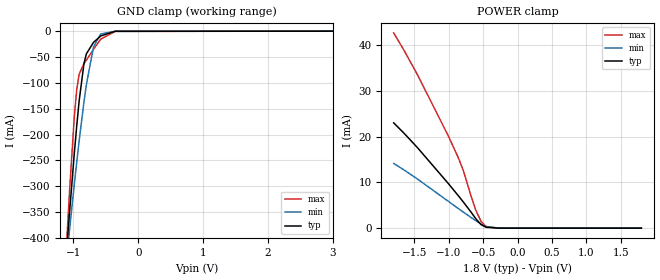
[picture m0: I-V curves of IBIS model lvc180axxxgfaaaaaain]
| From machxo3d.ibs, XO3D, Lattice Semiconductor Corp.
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|   Model lvc180axxxgfaaaaaain
[Model] lvc180axxxgfaaaaaain
Model_type Input
Polarity   Non-Inverting
Enable   Active-High
Vinl =  0.630V
Vinh =  1.170V
C_comp   4.200pF   3.800pF   7.500pF
[Temperature Range]   25.000   0.105k   -40.000
[Voltage Range]   1.800V   1.710V   1.890V
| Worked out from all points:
|   GND clamp passes 1 mA (typ) near -0.44 V on its own axis
|   POWER clamp passes 1 mA (typ) near -0.55 V on its own axis
[GND_clamp]
|Voltage   I(typ)   I(min)   I(max)
-1.8V     -1.677A    -1.372A    -2.207A
-1.097V   -411.7mA   -430.5mA   -393mA
-1.06V    -351mA     -384.7mA   -309.9mA
-986mV    -235.9mA   -295.9mA   -164.7mA
-949mV    -183mA     -253.4mA   -113.1mA
-912mV    -135mA     -212.5mA   -83.37mA
-838mV    -63.19mA   -137.2mA   -62.71mA
-801mV    -43.96mA   -103.8mA   -56.31mA
-690mV    -21.53mA   -30.09mA   -34.78mA
-579mV    -9.098mA   -5.388mA   -15.39mA
-357mV    -191.2uA   -96.8uA    -297.4uA
3.6V      109.7uA    43.1uA     257.2uA
[POWER_clamp]
|Voltage   I(typ)   I(min)   I(max)
-1.8V     23.01mA    14.15mA    42.67mA
-1.641V   20.61mA    12.64mA    38.63mA
-1.456V   17.62mA    10.75mA    33.57mA
-1.012V   9.862mA    5.935mA    20.34mA
-864mV    7.157mA    4.325mA    15.51mA
-790mV    5.765mA    3.532mA    12.71mA
-679mV    3.576mA    2.369mA    7.187mA
-605mV    2.036mA    1.625mA    3.879mA
-531mV    789uA      935.9uA    1.521mA
-457mV    197.5uA    375.1uA    332.7uA
-272mV    2.946uA    5.512uA    1.315uA
1.8V      0A         0A         0A
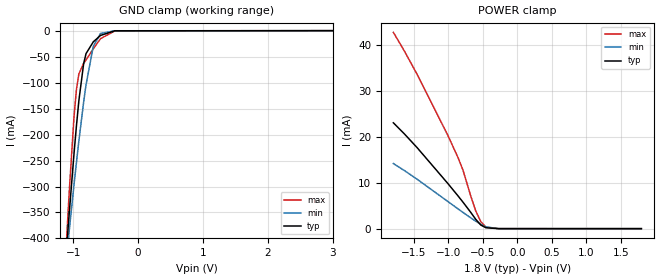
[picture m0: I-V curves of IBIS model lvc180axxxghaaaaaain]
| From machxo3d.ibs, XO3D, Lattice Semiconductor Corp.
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|   Model lvc180axxxghaaaaaain
[Model] lvc180axxxghaaaaaain
Model_type Input
Polarity   Non-Inverting
Enable   Active-High
Vinl =  0.630V
Vinh =  1.170V
C_comp   4.200pF   3.800pF   7.500pF
[Temperature Range]   25.000   0.105k   -40.000
[Voltage Range]   1.800V   1.710V   1.890V
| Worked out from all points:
|   GND clamp passes 1 mA (typ) near -0.44 V on its own axis
|   POWER clamp passes 1 mA (typ) near -0.55 V on its own axis
[GND_clamp]
|Voltage   I(typ)   I(min)   I(max)
-1.8V     -1.677A    -1.372A    -2.207A
-1.097V   -411.7mA   -430.5mA   -393mA
-1.06V    -351mA     -384.7mA   -309.9mA
-986mV    -235.9mA   -295.9mA   -164.8mA
-949mV    -183mA     -253.4mA   -113.1mA
-912mV    -135mA     -212.5mA   -83.39mA
-838mV    -63.2mA    -137.2mA   -62.73mA
-801mV    -43.97mA   -103.8mA   -56.32mA
-690mV    -21.54mA   -30.09mA   -34.79mA
-579mV    -9.102mA   -5.388mA   -15.4mA
-357mV    -191.3uA   -96.81uA   -298.1uA
3.6V      109.7uA    43.11uA    257.2uA
[POWER_clamp]
|Voltage   I(typ)   I(min)   I(max)
-1.8V     23.01mA    14.15mA    42.67mA
-1.641V   20.61mA    12.64mA    38.63mA
-1.456V   17.62mA    10.75mA    33.57mA
-1.012V   9.864mA    5.936mA    20.36mA
-864mV    7.162mA    4.325mA    15.53mA
-790mV    5.771mA    3.533mA    12.74mA
-679mV    3.583mA    2.37mA     7.204mA
-605mV    2.041mA    1.626mA    3.889mA
-531mV    791.7uA    936.7uA    1.526mA
-457mV    198.5uA    375.7uA    334.5uA
-272mV    2.958uA    5.534uA    1.322uA
1.8V      0A         0A         0A
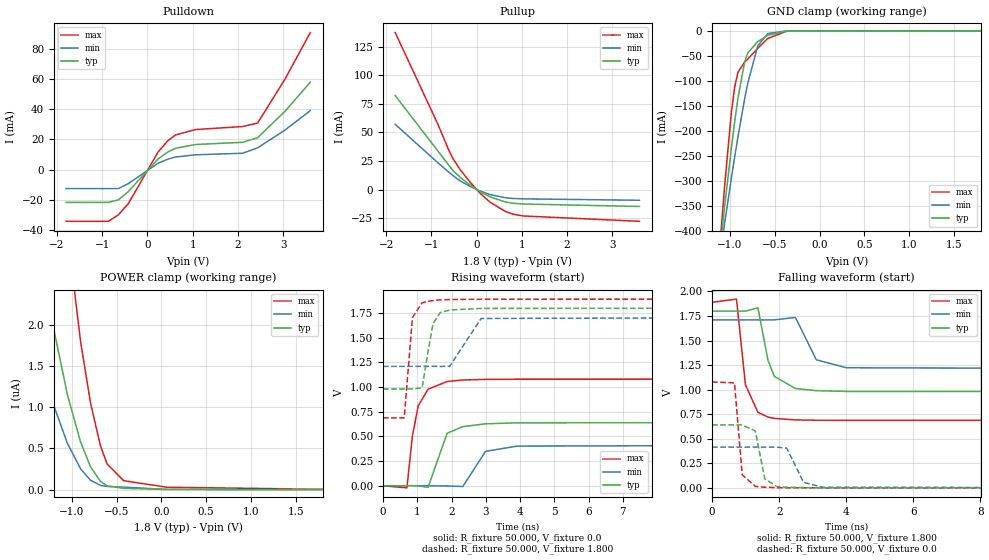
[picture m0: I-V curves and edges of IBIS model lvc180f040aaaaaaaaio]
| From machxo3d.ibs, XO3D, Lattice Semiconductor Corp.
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|   Model lvc180f040aaaaaaaaio
[Model] lvc180f040aaaaaaaaio
Model_type I/O
Polarity   Non-Inverting
Enable   Active-Low
Vinl =  0.630V
Vinh =  1.170V
Vmeas =  0.900V
Cref =  0.0F
Rref =  1.000M
Vref =  0.0V
C_comp   4.200pF   3.800pF   7.500pF
[Temperature Range]   25.000   0.105k   -40.000
[Voltage Range]   1.800V   1.710V   1.890V
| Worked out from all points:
|   slope of the pulldown table from 0 to 0.27 V, typ, clamps not added: 34 ohm
|   slope of the pullup table from 0 to 0.27 V, typ, clamps not added: 45.6 ohm
|   GND clamp passes 1 mA (typ) near -0.44 V on its own axis
|   rising waveform, R_fixture 50.000, V_fixture 0.0: 20-80 % time 386ps typ, 449ps min, 308ps max; typ from 0 V to 0.641 V
|   rising waveform, R_fixture 50.000, V_fixture 1.800: 20-80 % time 236ps typ, 363ps min, 142ps max; typ from 0.98 V to 1.8 V
|   falling waveform, R_fixture 50.000, V_fixture 1.800: 20-80 % time 355ps typ, 431ps min, 279ps max; typ from 1.8 V to 0.98 V
|   falling waveform, R_fixture 50.000, V_fixture 0.0: 20-80 % time 191ps typ, 337ps min, 125ps max; typ from 0.641 V to 0 V
[Pulldown]
|Voltage   I(typ)   I(min)   I(max)
-1.8V     -21.78mA   -12.65mA   -34.34mA
-865mV    -21.78mA   -12.65mA   -34.34mA
-645mV    -20.15mA   -12.65mA   -30.11mA
-425mV    -14.65mA   -9.378mA   -22.7mA
235mV     7.083mA    4.214mA    11.64mA
455mV     11.78mA    6.962mA    19.3mA
620mV     14.1mA     8.304mA    22.95mA
1.06V     16.63mA    9.799mA    26.56mA
2.105V    18.09mA    10.84mA    28.56mA
2.435V    21.14mA    14.41mA    30.89mA
3.04V     38.65mA    26.21mA    59.99mA
3.6V      57.99mA    39.16mA    90.94mA
[Pullup]
|Voltage   I(typ)   I(min)   I(max)
-1.8V     82.19mA    57.08mA    137.3mA
-855mV    33.69mA    23.41mA    57.06mA
-635mV    22.29mA    15.89mA    36.23mA
-525mV    16.8mA     12.27mA    27.21mA
-360mV    10.56mA    7.514mA    17.17mA
-140mV    3.787mA    2.633mA    6.305mA
80mV      -1.961mA   -1.338mA   -3.329mA
300mV     -6.456mA   -4.362mA   -11.09mA
630mV     -10.81mA   -7.147mA   -19.03mA
795mV     -11.95mA   -7.796mA   -21.4mA
1.015V    -12.62mA   -8.118mA   -23.07mA
3.6V      -14.81mA   -9.37mA    -27.76mA
[GND_clamp]
|Voltage   I(typ)   I(min)   I(max)
-1.8V     -1.677A    -1.372A    -2.207A
-1.097V   -411.6mA   -430.5mA   -392.9mA
-1.06V    -351mA     -384.7mA   -309.8mA
-986mV    -235.9mA   -295.9mA   -164.7mA
-949mV    -183mA     -253.4mA   -113mA
-912mV    -135mA     -212.5mA   -83.33mA
-838mV    -63.16mA   -137.2mA   -62.66mA
-801mV    -43.93mA   -103.8mA   -56.25mA
-690mV    -21.49mA   -30.06mA   -34.72mA
-579mV    -9.043mA   -5.343mA   -15.31mA
-357mV    -110.3uA   -52.32uA   -166.6uA
1.8V      0A         0A         0A
[POWER_clamp]
|Voltage   I(typ)   I(min)   I(max)
-1.8V     6.918uA    4.075uA    15.53uA
-1.641V   5.335uA    3.081uA    12.17uA
-1.382V   3.16uA     1.741uA    7.507uA
-1.197V   1.931uA    1.01uA     4.843uA
-1.049V   1.156uA    564.3nA    3.128uA
-901mV    576.3nA    251.7nA    1.796uA
-790mV    276.2nA    113.2nA    1.051uA
-679mV    99.59nA    51.79nA    530.4nA
-605mV    45.38nA    37.91nA    310.9nA
-420mV    15.41nA    30.1nA     108.2nA
61mV      1.594nA    2.49nA     28.82nA
1.8V      0A         0A         4.229nA
[Ramp]
| variable   typ   min   max
dV/dt_r   0.384/0.386n   0.249/0.445n   0.647/0.307n
dV/dt_f   0.492/0.355n   0.301/0.435n   0.721/0.279n
R_load = 50.000
[Rising Waveform]
R_fixture= 50.000
V_fixture= 0.0
V_fixture_min= 0.0
V_fixture_max= 0.0
|time   V(typ)   V(min)   V(max)
0s        4.812nV    48.48nV    2.958nV
699ps     19.91uV    27.31uV    -21.31mV
857ps     223.6uV    27.31uV    498.6mV
1.026ns   -749.7uV   2.355uV    807.6mV
1.316ns   -15.69mV   112.9uV    977.8mV
1.871ns   531.1mV    -2.339mV   1.056V
2.33ns    598.9mV    -7.379mV   1.071V
2.993ns   627.3mV    348.1mV    1.077V
3.921ns   637.4mV    401.9mV    1.079V
20ns      640.6mV    415.2mV    1.079V
[Rising Waveform]
R_fixture= 50.000
V_fixture= 1.800
V_fixture_min= 1.710
V_fixture_max= 1.890
|time   V(typ)   V(min)   V(max)
0s        979.8mV    1.209V     687.7mV
620ps     979.8mV    1.209V     687.8mV
860ps     980.6mV    1.209V     1.703V
1.141ns   990.3mV    1.209V     1.853V
1.318ns   1.365V     1.209V     1.868V
1.461ns   1.641V     1.21V      1.875V
1.669ns   1.753V     1.208V     1.882V
1.95ns    1.78V      1.211V     1.886V
2.864ns   1.796V     1.694V     1.889V
20ns      1.8V       1.71V      1.89V
[Falling Waveform]
R_fixture= 50.000
V_fixture= 1.800
V_fixture_min= 1.710
V_fixture_max= 1.890
|time   V(typ)   V(min)   V(max)
0s        1.8V       1.71V      1.89V
727ps     1.8V       1.71V      1.922V
993ps     1.8V       1.71V      1.05V
1.366ns   1.833V     1.71V      769.3mV
1.666ns   1.299V     1.71V      720.8mV
1.858ns   1.135V     1.711V     707.2mV
2.484ns   1.012V     1.735V     692.1mV
3.108ns   989.7mV    1.304V     688.6mV
4.007ns   982mV      1.223V     687.8mV
20ns      979.7mV    1.209V     687.6mV
[Falling Waveform]
R_fixture= 50.000
V_fixture= 0.0
V_fixture_min= 0.0
V_fixture_max= 0.0
|time   V(typ)   V(min)   V(max)
0s        640.6mV    415.2mV    1.079V
667ps     640.7mV    415.2mV    1.069V
898ps     640.4mV    415.2mV    132.7mV
1.288ns   579.4mV    415.2mV    15.08mV
1.571ns   92.34mV    415.1mV    6.669mV
1.925ns   13.86mV    414.7mV    2.223mV
2.223ns   6.601mV    404.8mV    908.6uV
2.728ns   2.36mV     56.11mV    285.3uV
3.294ns   792uV      6.444mV    115uV
20ns      -71.67nV   -68.73nV   -597.1nV
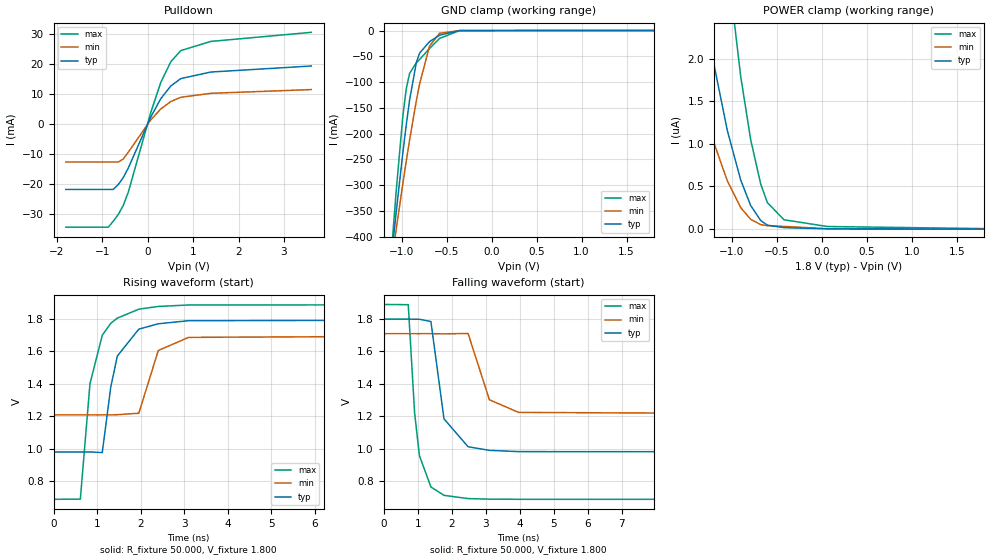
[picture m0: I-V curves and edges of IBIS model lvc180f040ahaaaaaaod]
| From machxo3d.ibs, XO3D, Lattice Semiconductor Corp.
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|   Model lvc180f040ahaaaaaaod
[Model] lvc180f040ahaaaaaaod
Model_type I/O_open_drain
Polarity   Non-Inverting
Enable   Active-Low
Vinl =  0.630V
Vinh =  1.170V
Vmeas =  0.900V
Cref =  0.0F
Rref = 10.00k
Vref = 1.80V
C_comp   4.200pF   3.800pF   7.500pF
[Temperature Range]   25.000   0.105k   -40.000
[Voltage Range]   1.800V   1.710V   1.890V
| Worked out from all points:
|   slope of the pulldown table from 0 to 0.27 V, typ, clamps not added: 34 ohm
|   GND clamp passes 1 mA (typ) near -0.44 V on its own axis
|   rising waveform, R_fixture 50.000, V_fixture 1.800: 20-80 % time 346ps typ, 361ps min, 349ps max; typ from 0.98 V to 1.8 V
|   falling waveform, R_fixture 50.000, V_fixture 1.800: 20-80 % time 364ps typ, 447ps min, 276ps max; typ from 1.8 V to 0.98 V
[Pulldown]
|Voltage   I(typ)   I(min)   I(max)
-1.8V     -21.78mA   -12.65mA   -34.34mA
-865mV    -21.78mA   -12.65mA   -34.34mA
-755mV    -21.78mA   -12.65mA   -32.34mA
-645mV    -20.15mA   -12.65mA   -30.11mA
-535mV    -17.81mA   -11.66mA   -27.1mA
-425mV    -14.65mA   -9.378mA   -22.7mA
70mV      2.34mA     1.397mA    3.847mA
290mV     8.429mA    5.007mA    13.84mA
510mV     12.66mA    7.475mA    20.72mA
730mV     15.12mA    8.894mA    24.44mA
1.39V     17.3mA     10.22mA    27.49mA
3.6V      19.31mA    11.46mA    30.52mA
[GND_clamp]
|Voltage   I(typ)   I(min)   I(max)
-1.8V     -1.677A    -1.372A    -2.207A
-1.097V   -411.6mA   -430.5mA   -392.9mA
-1.06V    -351mA     -384.7mA   -309.8mA
-986mV    -235.9mA   -295.9mA   -164.7mA
-949mV    -183mA     -253.4mA   -113mA
-912mV    -135mA     -212.5mA   -83.33mA
-838mV    -63.16mA   -137.2mA   -62.66mA
-801mV    -43.93mA   -103.8mA   -56.25mA
-690mV    -21.49mA   -30.06mA   -34.72mA
-579mV    -9.043mA   -5.343mA   -15.31mA
-357mV    -110.3uA   -52.32uA   -166.6uA
1.8V      0A         0A         0A
[POWER_clamp]
|Voltage   I(typ)   I(min)   I(max)
-1.8V     6.918uA    4.075uA    15.53uA
-1.641V   5.335uA    3.081uA    12.17uA
-1.382V   3.16uA     1.741uA    7.507uA
-1.197V   1.931uA    1.01uA     4.843uA
-1.049V   1.156uA    564.3nA    3.128uA
-901mV    576.3nA    251.7nA    1.796uA
-790mV    276.2nA    113.2nA    1.051uA
-679mV    99.59nA    51.79nA    530.4nA
-605mV    45.38nA    37.91nA    310.9nA
-420mV    15.41nA    30.11nA    108.2nA
61mV      1.594nA    2.49nA     28.82nA
1.8V      0A         0A         4.229nA
[Ramp]
| variable   typ   min   max
dV/dt_r   0.492/0.346n   0.301/0.359n   0.721/0.348n
dV/dt_f   0.492/0.361n   0.301/0.446n   0.721/0.278n
R_load = 50.000
[Rising Waveform]
R_fixture= 50.000
V_fixture= 1.800
V_fixture_min= 1.710
V_fixture_max= 1.890
|time   V(typ)   V(min)   V(max)
0s        979.8mV    1.209V     687.7mV
615ps     979.8mV    1.209V     689mV
836ps     980.2mV    1.209V     1.401V
1.118ns   976.4mV    1.209V     1.7V
1.313ns   1.38V      1.209V     1.774V
1.464ns   1.572V     1.21V      1.806V
1.957ns   1.738V     1.219V     1.861V
2.403ns   1.771V     1.606V     1.878V
3.097ns   1.79V      1.687V     1.887V
20ns      1.8V       1.71V      1.89V
[Falling Waveform]
R_fixture= 50.000
V_fixture= 1.800
V_fixture_min= 1.710
V_fixture_max= 1.890
|time   V(typ)   V(min)   V(max)
0s        1.8V       1.71V      1.89V
723ps     1.8V       1.71V      1.889V
910ps     1.799V     1.71V      1.221V
1.051ns   1.799V     1.71V      957.6mV
1.389ns   1.785V     1.71V      764mV
1.774ns   1.184V     1.709V     712.1mV
2.482ns   1.012V     1.711V     692.2mV
3.109ns   989.9mV    1.302V     688.7mV
3.968ns   982.1mV    1.224V     687.8mV
20ns      979.7mV    1.209V     687.6mV
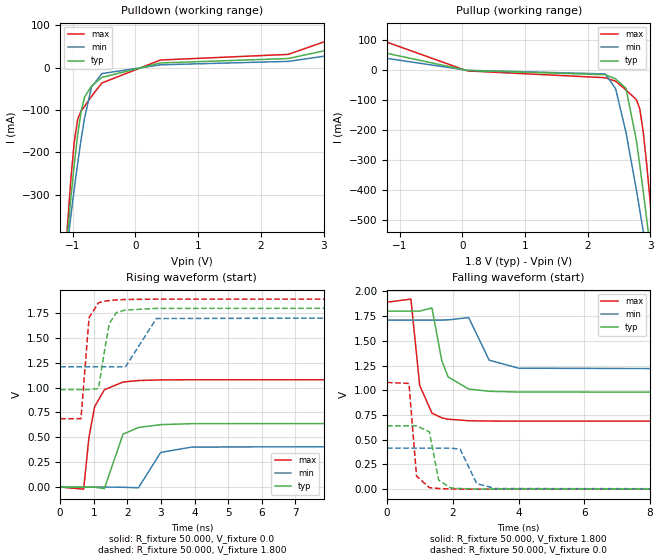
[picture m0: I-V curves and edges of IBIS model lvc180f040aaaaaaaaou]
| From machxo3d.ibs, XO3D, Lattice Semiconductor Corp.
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|   Model lvc180f040aaaaaaaaou
[Model] lvc180f040aaaaaaaaou
Model_type Output
Polarity   Non-Inverting
Enable   Active-High
Vmeas =  0.900V
Cref =  0.0F
Rref =  1.000M
Vref =  0.0V
C_comp   4.200pF   3.800pF   7.500pF
[Temperature Range]   25.000   0.105k   -40.000
[Voltage Range]   1.800V   1.710V   1.890V
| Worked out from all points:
|   slope of the pulldown table from 0 to 0.27 V, typ, clamps not added: 34 ohm
|   slope of the pullup table from 0 to 0.27 V, typ, clamps not added: 45.6 ohm
|   rising waveform, R_fixture 50.000, V_fixture 0.0: 20-80 % time 386ps typ, 449ps min, 308ps max; typ from 0 V to 0.641 V
|   rising waveform, R_fixture 50.000, V_fixture 1.800: 20-80 % time 236ps typ, 363ps min, 142ps max; typ from 0.98 V to 1.8 V
|   falling waveform, R_fixture 50.000, V_fixture 1.800: 20-80 % time 355ps typ, 431ps min, 279ps max; typ from 1.8 V to 0.98 V
|   falling waveform, R_fixture 50.000, V_fixture 0.0: 20-80 % time 191ps typ, 337ps min, 125ps max; typ from 0.641 V to 0 V
[Pulldown]
|Voltage   I(typ)   I(min)   I(max)
-1.8V     -1.678A    -1.372A    -2.208A
-1.085V   -396mA     -417.6mA   -375.7mA
-1.03V    -308.9mA   -350.6mA   -264.3mA
-975mV    -228.3mA   -286mA     -175.1mA
-920mV    -158.1mA   -224.8mA   -121.7mA
-865mV    -103.1mA   -168.3mA   -102.1mA
-810mV    -69.12mA   -118.3mA   -91.22mA
-700mV    -43.91mA   -46.17mA   -67.96mA
-535mV    -23.24mA   -14.27mA   -36.42mA
400mV     10.77mA    6.38mA     17.68mA
2.435V    21.14mA    14.41mA    30.89mA
3.6V      58mA       39.16mA    90.95mA
[Pullup]
|Voltage   I(typ)   I(min)   I(max)
-1.8V     82.2mA     57.09mA    137.3mA
80mV      -1.961mA   -1.338mA   -3.329mA
2.28V     -16.08mA   -13.43mA   -26.16mA
2.445V    -29.88mA   -63.06mA   -37.88mA
2.61V     -61.72mA   -208.6mA   -66.88mA
2.775V    -234mA     -399.9mA   -99.24mA
2.83V     -317.5mA   -468.5mA   -130.4mA
2.885V    -406.2mA   -538.5mA   -206.7mA
2.94V     -498.2mA   -609.7mA   -315mA
2.995V    -592.6mA   -681.8mA   -438.3mA
3.05V     -688.8mA   -754.7mA   -569.3mA
3.6V      -1.692A    -1.506A    -1.994A
[Ramp]
| variable   typ   min   max
dV/dt_r   0.384/0.386n   0.249/0.445n   0.647/0.307n
dV/dt_f   0.492/0.355n   0.301/0.435n   0.721/0.279n
R_load = 50.000
[Rising Waveform]
R_fixture= 50.000
V_fixture= 0.0
V_fixture_min= 0.0
V_fixture_max= 0.0
|time   V(typ)   V(min)   V(max)
0s        4.812nV    48.48nV    2.958nV
699ps     19.91uV    27.31uV    -21.31mV
857ps     223.6uV    27.31uV    498.6mV
1.026ns   -749.7uV   2.355uV    807.6mV
1.316ns   -15.69mV   112.9uV    977.8mV
1.871ns   531.1mV    -2.339mV   1.056V
2.33ns    598.9mV    -7.379mV   1.071V
2.993ns   627.3mV    348.1mV    1.077V
3.921ns   637.4mV    401.9mV    1.079V
20ns      640.6mV    415.2mV    1.079V
[Rising Waveform]
R_fixture= 50.000
V_fixture= 1.800
V_fixture_min= 1.710
V_fixture_max= 1.890
|time   V(typ)   V(min)   V(max)
0s        979.8mV    1.209V     687.7mV
620ps     979.8mV    1.209V     687.8mV
860ps     980.6mV    1.209V     1.703V
1.141ns   990.3mV    1.209V     1.853V
1.318ns   1.365V     1.209V     1.868V
1.461ns   1.641V     1.21V      1.875V
1.669ns   1.753V     1.208V     1.882V
1.95ns    1.78V      1.211V     1.886V
2.864ns   1.796V     1.694V     1.889V
20ns      1.8V       1.71V      1.89V
[Falling Waveform]
R_fixture= 50.000
V_fixture= 1.800
V_fixture_min= 1.710
V_fixture_max= 1.890
|time   V(typ)   V(min)   V(max)
0s        1.8V       1.71V      1.89V
727ps     1.8V       1.71V      1.922V
993ps     1.8V       1.71V      1.05V
1.366ns   1.833V     1.71V      769.3mV
1.666ns   1.299V     1.71V      720.8mV
1.858ns   1.135V     1.711V     707.2mV
2.484ns   1.012V     1.735V     692.1mV
3.108ns   989.7mV    1.304V     688.6mV
4.007ns   982mV      1.223V     687.8mV
20ns      979.7mV    1.209V     687.6mV
[Falling Waveform]
R_fixture= 50.000
V_fixture= 0.0
V_fixture_min= 0.0
V_fixture_max= 0.0
|time   V(typ)   V(min)   V(max)
0s        640.6mV    415.2mV    1.079V
667ps     640.7mV    415.2mV    1.069V
898ps     640.4mV    415.2mV    132.7mV
1.288ns   579.4mV    415.2mV    15.08mV
1.571ns   92.34mV    415.1mV    6.669mV
1.925ns   13.86mV    414.7mV    2.223mV
2.223ns   6.601mV    404.8mV    908.6uV
2.728ns   2.36mV     56.11mV    285.3uV
3.294ns   792uV      6.444mV    115uV
20ns      -71.67nV   -68.73nV   -597.1nV
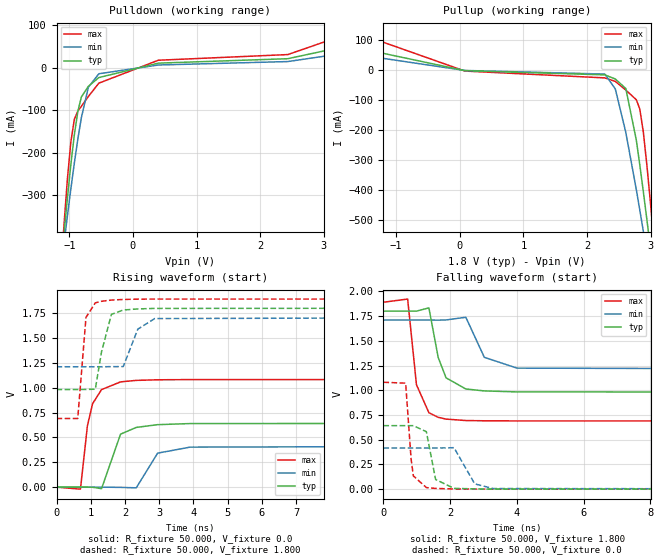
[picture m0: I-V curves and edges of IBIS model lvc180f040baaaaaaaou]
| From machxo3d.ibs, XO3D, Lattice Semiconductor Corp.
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|   Model lvc180f040baaaaaaaou
[Model] lvc180f040baaaaaaaou
Model_type Output
Polarity   Non-Inverting
Enable   Active-High
Vmeas =  0.900V
Cref =  0.0F
Rref =  1.000M
Vref =  0.0V
C_comp   4.200pF   3.800pF   7.500pF
[Temperature Range]   25.000   0.105k   -40.000
[Voltage Range]   1.800V   1.710V   1.890V
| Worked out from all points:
|   slope of the pulldown table from 0 to 0.27 V, typ, clamps not added: 34 ohm
|   slope of the pullup table from 0 to 0.27 V, typ, clamps not added: 45.5 ohm
|   rising waveform, R_fixture 50.000, V_fixture 0.0: 20-80 % time 385ps typ, 449ps min, 304ps max; typ from 0.001 V to 0.642 V
|   rising waveform, R_fixture 50.000, V_fixture 1.800: 20-80 % time 236ps typ, 364ps min, 142ps max; typ from 0.981 V to 1.8 V
|   falling waveform, R_fixture 50.000, V_fixture 1.800: 20-80 % time 355ps typ, 442ps min, 281ps max; typ from 1.8 V to 0.981 V
|   falling waveform, R_fixture 50.000, V_fixture 0.0: 20-80 % time 193ps typ, 338ps min, 125ps max; typ from 0.642 V to 0.001 V
[Pulldown]
|Voltage   I(typ)   I(min)   I(max)
-1.8V     -1.678A    -1.372A    -2.208A
-1.085V   -396mA     -417.6mA   -375.7mA
-1.03V    -309mA     -350.6mA   -264.3mA
-975mV    -228.3mA   -286mA     -175.1mA
-920mV    -158.1mA   -224.8mA   -121.7mA
-865mV    -103.2mA   -168.3mA   -102.1mA
-810mV    -69.13mA   -118.3mA   -91.25mA
-700mV    -43.93mA   -46.18mA   -67.99mA
-535mV    -23.26mA   -14.28mA   -36.46mA
400mV     10.74mA    6.36mA     17.6mA
2.435V    21.19mA    14.46mA    30.93mA
3.6V      58.68mA    40.13mA    91.49mA
[Pullup]
|Voltage   I(typ)   I(min)   I(max)
-1.8V     82.9mA     57.94mA    138mA
80mV      -1.967mA   -1.342mA   -3.339mA
2.28V     -16.11mA   -13.44mA   -26.22mA
2.445V    -29.9mA    -63.07mA   -37.92mA
2.61V     -61.73mA   -208.6mA   -66.9mA
2.775V    -234mA     -399.9mA   -99.26mA
2.83V     -317.5mA   -468.5mA   -130.4mA
2.885V    -406.2mA   -538.5mA   -206.7mA
2.94V     -498.2mA   -609.7mA   -315.1mA
2.995V    -592.7mA   -681.9mA   -438.4mA
3.05V     -688.8mA   -754.7mA   -569.3mA
3.6V      -1.692A    -1.506A    -1.995A
[Ramp]
| variable   typ   min   max
dV/dt_r   0.385/0.386n   0.249/0.445n   0.648/0.306n
dV/dt_f   0.491/0.348n   0.300/0.435n   0.720/0.280n
R_load = 50.000
[Rising Waveform]
R_fixture= 50.000
V_fixture= 0.0
V_fixture_min= 0.0
V_fixture_max= 0.0
|time   V(typ)   V(min)   V(max)
0s        714.8uV    493.6uV    1.055mV
699ps     759.9uV    520.7uV    -19.82mV
902ps     866.5uV    520.7uV    615mV
1.053ns   -645.3uV   495.7uV    838.4mV
1.316ns   -14.52mV   609.6uV    980.5mV
1.871ns   532.8mV    -1.877mV   1.058V
2.33ns    600.6mV    -6.567mV   1.073V
2.955ns   628.2mV    342mV      1.079V
3.905ns   639.2mV    402.6mV    1.081V
20ns      642.4mV    416.2mV    1.081V
[Rising Waveform]
R_fixture= 50.000
V_fixture= 1.800
V_fixture_min= 1.710
V_fixture_max= 1.890
|time   V(typ)   V(min)   V(max)
0s        981.3mV    1.21V      690.2mV
620ps     981.3mV    1.21V      690.3mV
861ps     982.1mV    1.21V      1.706V
1.133ns   984.2mV    1.21V      1.852V
1.315ns   1.36V      1.21V      1.868V
1.604ns   1.736V     1.211V     1.88V
1.95ns    1.78V      1.212V     1.886V
2.376ns   1.791V     1.588V     1.889V
2.87ns    1.796V     1.694V     1.89V
20ns      1.8V       1.71V      1.89V
[Falling Waveform]
R_fixture= 50.000
V_fixture= 1.800
V_fixture_min= 1.710
V_fixture_max= 1.890
|time   V(typ)   V(min)   V(max)
0s        1.8V       1.71V      1.89V
727ps     1.8V       1.71V      1.922V
991ps     1.8V       1.71V      1.056V
1.364ns   1.833V     1.71V      772.9mV
1.643ns   1.331V     1.709V     726.7mV
1.878ns   1.126V     1.711V     708.8mV
2.471ns   1.013V     1.738V     694.1mV
3.025ns   993.6mV    1.333V     691.7mV
4.005ns   983.6mV    1.224V     690.3mV
20ns      981.3mV    1.21V      690.1mV
[Falling Waveform]
R_fixture= 50.000
V_fixture= 0.0
V_fixture_min= 0.0
V_fixture_max= 0.0
|time   V(typ)   V(min)   V(max)
0s        642.4mV    416.2mV    1.081V
667ps     642.5mV    416.1mV    1.072V
829ps     642.4mV    416.2mV    309.4mV
898ps     642.2mV    416.2mV    134.6mV
1.288ns   581.3mV    416.2mV    16.2mV
1.565ns   98.02mV    416mV      7.937mV
2.116ns   8.922mV    419.7mV    2.498mV
2.738ns   3.095mV    53.87mV    1.371mV
3.284ns   1.52mV     7.108mV    1.13mV
20ns      714.7uV    493.5uV    1.054mV
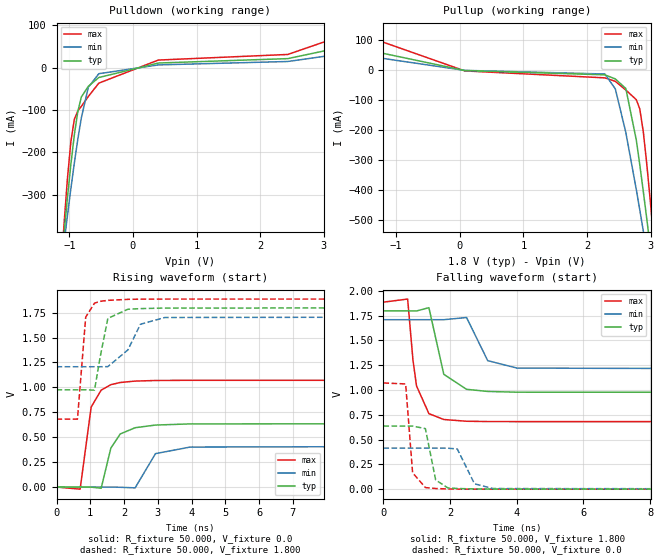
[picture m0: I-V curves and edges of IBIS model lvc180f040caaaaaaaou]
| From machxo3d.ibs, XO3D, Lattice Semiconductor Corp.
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|   Model lvc180f040caaaaaaaou
[Model] lvc180f040caaaaaaaou
Model_type Output
Polarity   Non-Inverting
Enable   Active-High
Vmeas =  0.900V
Cref =  0.0F
Rref =  1.000M
Vref =  0.0V
C_comp   4.200pF   3.800pF   7.500pF
[Temperature Range]   25.000   0.105k   -40.000
[Voltage Range]   1.800V   1.710V   1.890V
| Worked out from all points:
|   slope of the pulldown table from 0 to 0.27 V, typ, clamps not added: 33.8 ohm
|   slope of the pullup table from 0 to 0.27 V, typ, clamps not added: 45.6 ohm
|   rising waveform, R_fixture 50.000, V_fixture 0.0: 20-80 % time 383ps typ, 445ps min, 307ps max; typ from 0 V to 0.636 V
|   rising waveform, R_fixture 50.000, V_fixture 1.800: 20-80 % time 236ps typ, 366ps min, 143ps max; typ from 0.976 V to 1.8 V
|   falling waveform, R_fixture 50.000, V_fixture 1.800: 20-80 % time 354ps typ, 437ps min, 278ps max; typ from 1.8 V to 0.976 V
|   falling waveform, R_fixture 50.000, V_fixture 0.0: 20-80 % time 190ps typ, 336ps min, 124ps max; typ from 0.636 V to 0 V
[Pulldown]
|Voltage   I(typ)   I(min)   I(max)
-1.8V     -1.678A    -1.372A    -2.208A
-1.085V   -396mA     -417.6mA   -375.8mA
-1.03V    -309mA     -350.6mA   -264.4mA
-975mV    -228.4mA   -286mA     -175.1mA
-920mV    -158.2mA   -224.8mA   -121.7mA
-865mV    -103.2mA   -168.3mA   -102.1mA
-810mV    -69.16mA   -118.3mA   -91.29mA
-700mV    -43.96mA   -46.2mA    -68.03mA
-535mV    -23.3mA    -14.32mA   -36.51mA
400mV     10.84mA    6.409mA    17.83mA
2.435V    21.22mA    14.45mA    31.04mA
3.6V      58.16mA    39.24mA    91.28mA
[Pullup]
|Voltage   I(typ)   I(min)   I(max)
-1.8V     82.37mA    57.16mA    137.7mA
80mV      -1.86mA    -1.301mA   -3.087mA
2.28V     -16.16mA   -13.47mA   -26.29mA
2.445V    -29.93mA   -63.08mA   -37.97mA
2.61V     -61.75mA   -208.6mA   -66.94mA
2.775V    -234.1mA   -399.9mA   -99.28mA
2.83V     -317.5mA   -468.5mA   -130.4mA
2.885V    -406.2mA   -538.5mA   -206.8mA
2.94V     -498.3mA   -609.7mA   -315.1mA
2.995V    -592.7mA   -681.9mA   -438.4mA
3.05V     -688.8mA   -754.7mA   -569.4mA
3.6V      -1.692A    -1.506A    -1.995A
[Ramp]
| variable   typ   min   max
dV/dt_r   0.382/0.383n   0.248/0.439n   0.643/0.306n
dV/dt_f   0.493/0.347n   0.301/0.434n   0.723/0.277n
R_load = 50.000
[Rising Waveform]
R_fixture= 50.000
V_fixture= 0.0
V_fixture_min= 0.0
V_fixture_max= 0.0
|time   V(typ)   V(min)   V(max)
0s        4.637nV    47.96nV    2.735nV
699ps     19.92uV    27.27uV    -21.25mV
1.026ns   -762.3uV   2.292uV    803.1mV
1.322ns   -11.91mV   112.7uV    972.2mV
1.609ns   391mV      -125.2uV   1.027V
1.886ns   532.6mV    -2.337mV   1.049V
2.327ns   595.2mV    -8.292mV   1.063V
2.931ns   622mV      335.3mV    1.069V
3.957ns   633.5mV    401.2mV    1.071V
20ns      636.4mV    413.8mV    1.071V
[Rising Waveform]
R_fixture= 50.000
V_fixture= 1.800
V_fixture_min= 1.710
V_fixture_max= 1.890
|time   V(typ)   V(min)   V(max)
0s        975.6mV    1.207V     681.2mV
620ps     975.6mV    1.207V     681.3mV
864ps     975.8mV    1.207V     1.705V
1.125ns   972.2mV    1.207V     1.845V
1.289ns   1.299V     1.207V     1.863V
1.52ns    1.692V     1.208V     1.873V
2.114ns   1.784V     1.376V     1.883V
2.484ns   1.79V      1.633V     1.885V
3.204ns   1.796V     1.701V     1.886V
20ns      1.798V     1.709V     1.886V
[Falling Waveform]
R_fixture= 50.000
V_fixture= 1.800
V_fixture_min= 1.710
V_fixture_max= 1.890
|time   V(typ)   V(min)   V(max)
0s        1.798V     1.709V     1.886V
727ps     1.798V     1.709V     1.917V
887ps     1.797V     1.709V     1.301V
993ps     1.797V     1.709V     1.042V
1.365ns   1.83V      1.709V     761.4mV
1.812ns   1.158V     1.709V     702.5mV
2.494ns   1.007V     1.731V     684.9mV
3.129ns   985.4mV    1.296V     681.9mV
4.008ns   977.8mV    1.221V     681.3mV
20ns      975.6mV    1.207V     681.1mV
[Falling Waveform]
R_fixture= 50.000
V_fixture= 0.0
V_fixture_min= 0.0
V_fixture_max= 0.0
|time   V(typ)   V(min)   V(max)
0s        636.4mV    413.8mV    1.071V
667ps     636.5mV    413.8mV    1.061V
876ps     636.2mV    413.8mV    165.5mV
1.26ns    610.4mV    413.8mV    16.01mV
1.568ns   92.61mV    413.7mV    6.519mV
1.928ns   13.38mV    413.3mV    2.105mV
2.216ns   6.668mV    405.7mV    1.037mV
2.732ns   2.388mV    54.29mV    243.8uV
3.279ns   804.7uV    6.583mV    84.17uV
20ns      -150.4nV   14.78nV    -412.4nV
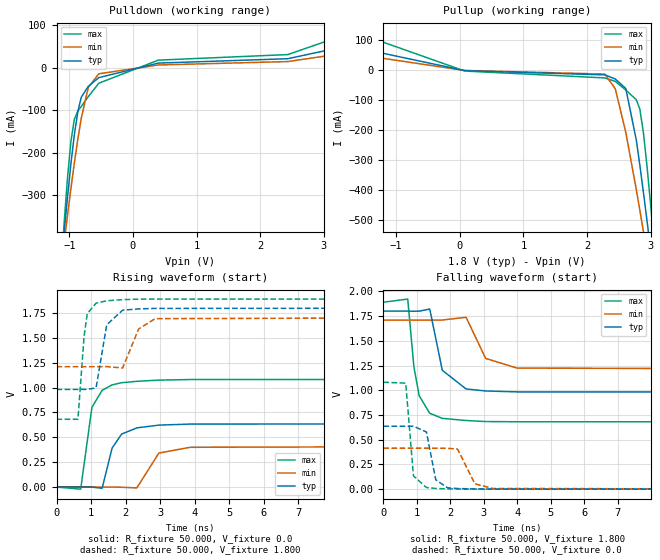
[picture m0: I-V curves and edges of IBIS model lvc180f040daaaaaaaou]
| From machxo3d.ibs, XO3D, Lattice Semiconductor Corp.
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|   Model lvc180f040daaaaaaaou
[Model] lvc180f040daaaaaaaou
Model_type Output
Polarity   Non-Inverting
Enable   Active-High
Vmeas =  0.900V
Cref =  0.0F
Rref =  1.000M
Vref =  0.0V
C_comp   4.200pF   3.800pF   7.500pF
[Temperature Range]   25.000   0.105k   -40.000
[Voltage Range]   1.800V   1.710V   1.890V
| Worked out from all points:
|   slope of the pulldown table from 0 to 0.27 V, typ, clamps not added: 33.8 ohm
|   slope of the pullup table from 0 to 0.27 V, typ, clamps not added: 45.5 ohm
|   rising waveform, R_fixture 50.000, V_fixture 0.0: 20-80 % time 383ps typ, 449ps min, 316ps max; typ from 0 V to 0.636 V
|   rising waveform, R_fixture 50.000, V_fixture 1.800: 20-80 % time 235ps typ, 364ps min, 144ps max; typ from 0.981 V to 1.8 V
|   falling waveform, R_fixture 50.000, V_fixture 1.800: 20-80 % time 355ps typ, 439ps min, 289ps max; typ from 1.8 V to 0.981 V
|   falling waveform, R_fixture 50.000, V_fixture 0.0: 20-80 % time 191ps typ, 336ps min, 126ps max; typ from 0.636 V to 0 V
[Pulldown]
|Voltage   I(typ)   I(min)   I(max)
-1.8V     -1.678A    -1.372A    -2.208A
-1.085V   -396mA     -417.6mA   -375.8mA
-1.03V    -309mA     -350.6mA   -264.4mA
-975mV    -228.4mA   -286mA     -175.1mA
-920mV    -158.2mA   -224.8mA   -121.7mA
-865mV    -103.2mA   -168.3mA   -102.1mA
-810mV    -69.16mA   -118.3mA   -91.29mA
-700mV    -43.96mA   -46.2mA    -68.03mA
-535mV    -23.3mA    -14.32mA   -36.51mA
400mV     10.84mA    6.409mA    17.83mA
2.435V    21.19mA    14.46mA    30.93mA
3.6V      58.68mA    40.13mA    91.49mA
[Pullup]
|Voltage   I(typ)   I(min)   I(max)
-1.8V     82.9mA     57.94mA    138mA
80mV      -1.967mA   -1.342mA   -3.339mA
2.28V     -16.16mA   -13.47mA   -26.29mA
2.445V    -29.93mA   -63.08mA   -37.97mA
2.61V     -61.75mA   -208.6mA   -66.94mA
2.775V    -234.1mA   -399.9mA   -99.28mA
2.83V     -317.5mA   -468.5mA   -130.4mA
2.885V    -406.2mA   -538.5mA   -206.8mA
2.94V     -498.3mA   -609.7mA   -315.1mA
2.995V    -592.7mA   -681.9mA   -438.4mA
3.05V     -688.8mA   -754.7mA   -569.4mA
3.6V      -1.692A    -1.506A    -1.995A
[Ramp]
| variable   typ   min   max
dV/dt_r   0.382/0.383n   0.248/0.439n   0.649/0.316n
dV/dt_f   0.491/0.348n   0.300/0.435n   0.725/0.287n
R_load = 50.000
[Rising Waveform]
R_fixture= 50.000
V_fixture= 0.0
V_fixture_min= 0.0
V_fixture_max= 0.0
|time   V(typ)   V(min)   V(max)
0s        4.637nV    47.96nV    2.735nV
699ps     19.92uV    27.24uV    -21.25mV
1.026ns   -762.3uV   2.286uV    803.1mV
1.322ns   -11.91mV   112.7uV    972.2mV
1.609ns   391mV      -125.2uV   1.027V
1.886ns   532.6mV    -2.337mV   1.049V
2.327ns   595.2mV    -8.292mV   1.063V
2.965ns   622.8mV    341.8mV    1.075V
3.87ns    633.1mV    399.7mV    1.081V
20ns      636.4mV    413.8mV    1.081V
[Rising Waveform]
R_fixture= 50.000
V_fixture= 1.800
V_fixture_min= 1.710
V_fixture_max= 1.890
|time   V(typ)   V(min)   V(max)
0s        981.3mV    1.21V      681.2mV
620ps     981.3mV    1.21V      681.3mV
799ps     981.5mV    1.21V      1.521V
890ps     982.5mV    1.21V      1.743V
1.145ns   996.2mV    1.21V      1.849V
1.454ns   1.632V     1.211V     1.873V
1.914ns   1.778V     1.197V     1.884V
2.376ns   1.791V     1.588V     1.889V
2.855ns   1.796V     1.693V     1.89V
20ns      1.8V       1.71V      1.89V
[Falling Waveform]
R_fixture= 50.000
V_fixture= 1.800
V_fixture_min= 1.710
V_fixture_max= 1.890
|time   V(typ)   V(min)   V(max)
0s        1.8V       1.71V      1.89V
727ps     1.8V       1.71V      1.922V
911ps     1.799V     1.71V      1.237V
1.07ns    1.8V       1.71V      944.4mV
1.385ns   1.821V     1.71V      767.3mV
1.76ns    1.202V     1.71V      715.9mV
2.471ns   1.013V     1.738V     694.3mV
3.055ns   992.9mV    1.322V     683.6mV
3.993ns   983.6mV    1.224V     681.6mV
20ns      981.3mV    1.21V      681.1mV
[Falling Waveform]
R_fixture= 50.000
V_fixture= 0.0
V_fixture_min= 0.0
V_fixture_max= 0.0
|time   V(typ)   V(min)   V(max)
0s        636.4mV    413.8mV    1.081V
667ps     636.5mV    413.8mV    1.072V
898ps     636.2mV    413.8mV    134.6mV
1.286ns   578.3mV    413.8mV    16.25mV
1.565ns   94.87mV    413.7mV    7.21mV
1.914ns   14mV       413.3mV    2.687mV
2.217ns   6.668mV    405.3mV    1.2mV
2.732ns   2.388mV    54.29mV    324uV
3.279ns   804.7uV    6.583mV    78.09uV
20ns      -150.4nV   14.78nV    -539.4nV
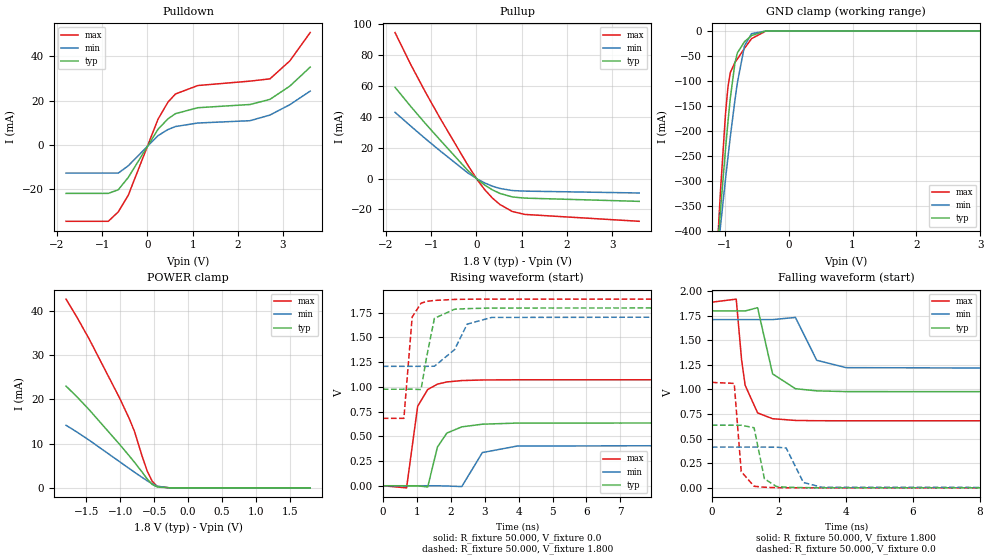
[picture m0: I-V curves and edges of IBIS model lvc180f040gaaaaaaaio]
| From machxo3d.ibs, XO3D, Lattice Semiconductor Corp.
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|   Model lvc180f040gaaaaaaaio
[Model] lvc180f040gaaaaaaaio
Model_type I/O
Polarity   Non-Inverting
Enable   Active-Low
Vinl =  0.630V
Vinh =  1.170V
Vmeas =  0.900V
Cref =  0.0F
Rref =  1.000M
Vref =  0.0V
C_comp   4.200pF   3.800pF   7.500pF
[Temperature Range]   25.000   0.105k   -40.000
[Voltage Range]   1.800V   1.710V   1.890V
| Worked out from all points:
|   slope of the pulldown table from 0 to 0.27 V, typ, clamps not added: 34 ohm
|   slope of the pullup table from 0 to 0.27 V, typ, clamps not added: 45.6 ohm
|   GND clamp passes 1 mA (typ) near -0.44 V on its own axis
|   POWER clamp passes 1 mA (typ) near -0.55 V on its own axis
|   rising waveform, R_fixture 50.000, V_fixture 0.0: 20-80 % time 383ps typ, 445ps min, 307ps max; typ from 0 V to 0.636 V
|   rising waveform, R_fixture 50.000, V_fixture 1.800: 20-80 % time 236ps typ, 366ps min, 143ps max; typ from 0.976 V to 1.8 V
|   falling waveform, R_fixture 50.000, V_fixture 1.800: 20-80 % time 354ps typ, 437ps min, 278ps max; typ from 1.8 V to 0.976 V
|   falling waveform, R_fixture 50.000, V_fixture 0.0: 20-80 % time 190ps typ, 336ps min, 124ps max; typ from 0.636 V to 0 V
[Pulldown]
|Voltage   I(typ)   I(min)   I(max)
-1.8V     -21.78mA   -12.65mA   -34.34mA
-865mV    -21.78mA   -12.65mA   -34.34mA
-645mV    -20.15mA   -12.65mA   -30.11mA
-425mV    -14.65mA   -9.378mA   -22.7mA
235mV     7.083mA    4.214mA    11.64mA
455mV     11.78mA    6.962mA    19.3mA
620mV     14.1mA     8.304mA    22.95mA
1.115V    16.77mA    9.887mA    26.76mA
2.27V     18.22mA    10.93mA    28.74mA
2.71V     20.53mA    13.47mA    29.76mA
3.15V     26.5mA     18.14mA    37.84mA
3.6V      35.04mA    24.25mA    50.59mA
[Pullup]
|Voltage   I(typ)   I(min)   I(max)
-1.8V     59.24mA    42.97mA    94.75mA
-1.46V    47.04mA    34.23mA    74.42mA
-1.13V    35.75mA    25.91mA    56.18mA
-800mV    24.9mA     17.87mA    38.97mA
-195mV    5.382mA    3.762mA    8.912mA
25mV      -631.9uA   -432.1uA   -1.07mA
190mV     -4.372mA   -2.969mA   -7.464mA
355mV     -7.378mA   -4.969mA   -12.72mA
520mV     -9.667mA   -6.446mA   -16.87mA
795mV     -11.95mA   -7.796mA   -21.4mA
1.07V     -12.7mA    -8.16mA    -23.29mA
3.6V      -14.81mA   -9.369mA   -27.75mA
[GND_clamp]
|Voltage   I(typ)   I(min)   I(max)
-1.8V     -1.677A    -1.372A    -2.207A
-1.097V   -411.7mA   -430.5mA   -393mA
-1.06V    -351mA     -384.7mA   -309.9mA
-986mV    -235.9mA   -295.9mA   -164.8mA
-949mV    -183mA     -253.4mA   -113.1mA
-912mV    -135mA     -212.5mA   -83.39mA
-838mV    -63.2mA    -137.2mA   -62.73mA
-801mV    -43.97mA   -103.8mA   -56.32mA
-690mV    -21.54mA   -30.09mA   -34.79mA
-579mV    -9.102mA   -5.388mA   -15.4mA
-357mV    -191.3uA   -96.81uA   -298.1uA
3.6V      109.7uA    43.11uA    257.2uA
[POWER_clamp]
|Voltage   I(typ)   I(min)   I(max)
-1.8V     23.01mA    14.15mA    42.67mA
-1.641V   20.61mA    12.64mA    38.63mA
-1.456V   17.62mA    10.75mA    33.57mA
-1.012V   9.864mA    5.936mA    20.36mA
-864mV    7.162mA    4.325mA    15.53mA
-790mV    5.771mA    3.533mA    12.74mA
-679mV    3.583mA    2.37mA     7.204mA
-605mV    2.041mA    1.626mA    3.889mA
-531mV    791.7uA    936.7uA    1.526mA
-457mV    198.5uA    375.7uA    334.5uA
-272mV    2.958uA    5.534uA    1.322uA
1.8V      0A         0A         0A
[Ramp]
| variable   typ   min   max
dV/dt_r   0.382/0.383n   0.248/0.439n   0.643/0.306n
dV/dt_f   0.493/0.347n   0.301/0.434n   0.723/0.277n
R_load = 50.000
[Rising Waveform]
R_fixture= 50.000
V_fixture= 0.0
V_fixture_min= 0.0
V_fixture_max= 0.0
|time   V(typ)   V(min)   V(max)
0s        4.637nV    47.96nV    2.735nV
699ps     19.92uV    27.27uV    -21.25mV
1.026ns   -762.3uV   2.292uV    803.1mV
1.322ns   -11.91mV   112.7uV    972.2mV
1.609ns   391mV      -125.2uV   1.027V
1.886ns   532.6mV    -2.337mV   1.049V
2.327ns   595.2mV    -8.292mV   1.063V
2.931ns   622mV      335.3mV    1.069V
3.957ns   633.5mV    401.2mV    1.071V
20ns      636.4mV    413.8mV    1.071V
[Rising Waveform]
R_fixture= 50.000
V_fixture= 1.800
V_fixture_min= 1.710
V_fixture_max= 1.890
|time   V(typ)   V(min)   V(max)
0s        975.6mV    1.207V     681.2mV
620ps     975.6mV    1.207V     681.3mV
864ps     975.8mV    1.207V     1.705V
1.125ns   972.2mV    1.207V     1.845V
1.289ns   1.299V     1.207V     1.863V
1.52ns    1.692V     1.208V     1.873V
2.114ns   1.784V     1.376V     1.883V
2.484ns   1.79V      1.633V     1.885V
3.204ns   1.796V     1.701V     1.886V
20ns      1.798V     1.709V     1.886V
[Falling Waveform]
R_fixture= 50.000
V_fixture= 1.800
V_fixture_min= 1.710
V_fixture_max= 1.890
|time   V(typ)   V(min)   V(max)
0s        1.798V     1.709V     1.886V
727ps     1.798V     1.709V     1.917V
887ps     1.797V     1.709V     1.301V
993ps     1.797V     1.709V     1.042V
1.365ns   1.83V      1.709V     761.4mV
1.812ns   1.158V     1.709V     702.5mV
2.494ns   1.007V     1.731V     684.9mV
3.129ns   985.4mV    1.296V     681.9mV
4.008ns   977.8mV    1.221V     681.3mV
20ns      975.6mV    1.207V     681.1mV
[Falling Waveform]
R_fixture= 50.000
V_fixture= 0.0
V_fixture_min= 0.0
V_fixture_max= 0.0
|time   V(typ)   V(min)   V(max)
0s        636.4mV    413.8mV    1.071V
667ps     636.5mV    413.8mV    1.061V
876ps     636.2mV    413.8mV    165.5mV
1.26ns    610.4mV    413.8mV    16.01mV
1.568ns   92.61mV    413.7mV    6.519mV
1.928ns   13.38mV    413.3mV    2.105mV
2.217ns   6.668mV    405.3mV    1.037mV
2.732ns   2.388mV    54.29mV    243.8uV
3.279ns   804.7uV    6.583mV    84.17uV
20ns      -150.4nV   14.78nV    -412.4nV
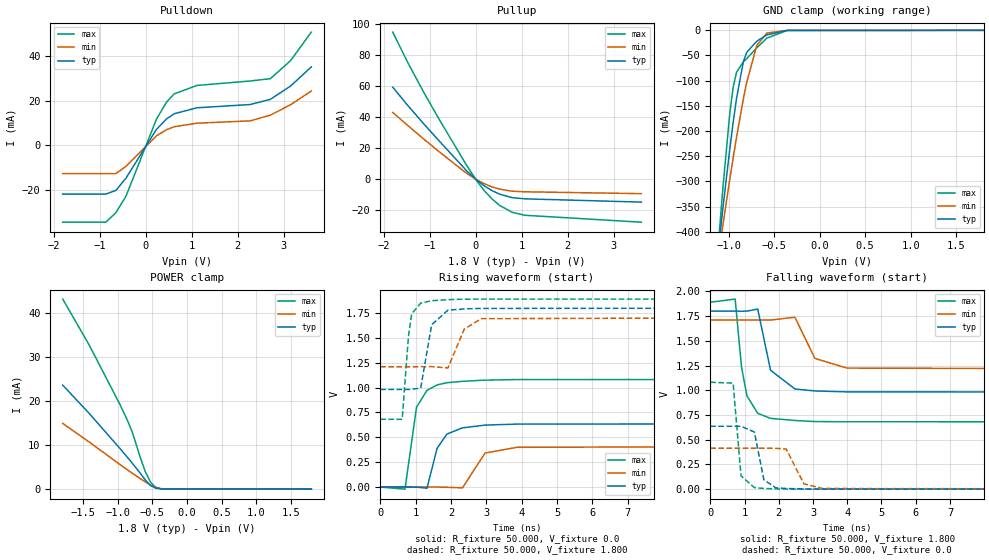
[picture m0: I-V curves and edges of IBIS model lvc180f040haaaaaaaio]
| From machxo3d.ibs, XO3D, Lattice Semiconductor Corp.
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|   Model lvc180f040haaaaaaaio
[Model] lvc180f040haaaaaaaio
Model_type I/O
Polarity   Non-Inverting
Enable   Active-Low
Vinl =  0.630V
Vinh =  1.170V
Vmeas =  0.900V
Cref =  0.0F
Rref =  1.000M
Vref =  0.0V
C_comp   4.200pF   3.800pF   7.500pF
[Temperature Range]   25.000   0.105k   -40.000
[Voltage Range]   1.800V   1.710V   1.890V
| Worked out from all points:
|   slope of the pulldown table from 0 to 0.27 V, typ, clamps not added: 34 ohm
|   slope of the pullup table from 0 to 0.27 V, typ, clamps not added: 45.6 ohm
|   GND clamp passes 1 mA (typ) near -0.44 V on its own axis
|   POWER clamp passes 1 mA (typ) near -0.54 V on its own axis
|   rising waveform, R_fixture 50.000, V_fixture 0.0: 20-80 % time 383ps typ, 449ps min, 316ps max; typ from 0 V to 0.636 V
|   rising waveform, R_fixture 50.000, V_fixture 1.800: 20-80 % time 235ps typ, 364ps min, 144ps max; typ from 0.981 V to 1.8 V
|   falling waveform, R_fixture 50.000, V_fixture 1.800: 20-80 % time 355ps typ, 439ps min, 289ps max; typ from 1.8 V to 0.981 V
|   falling waveform, R_fixture 50.000, V_fixture 0.0: 20-80 % time 191ps typ, 336ps min, 126ps max; typ from 0.636 V to 0 V
[Pulldown]
|Voltage   I(typ)   I(min)   I(max)
-1.8V     -21.78mA   -12.65mA   -34.34mA
-865mV    -21.78mA   -12.65mA   -34.34mA
-645mV    -20.15mA   -12.65mA   -30.11mA
-425mV    -14.65mA   -9.378mA   -22.7mA
235mV     7.083mA    4.214mA    11.64mA
455mV     11.78mA    6.962mA    19.3mA
620mV     14.1mA     8.304mA    22.95mA
1.115V    16.77mA    9.887mA    26.76mA
2.27V     18.22mA    10.93mA    28.74mA
2.71V     20.53mA    13.47mA    29.77mA
3.15V     26.5mA     18.14mA    37.84mA
3.6V      35.03mA    24.26mA    50.59mA
[Pullup]
|Voltage   I(typ)   I(min)   I(max)
-1.8V     59.25mA    42.99mA    94.75mA
-1.46V    47.05mA    34.24mA    74.42mA
-1.13V    35.75mA    25.91mA    56.18mA
-800mV    24.9mA     17.87mA    38.97mA
-195mV    5.382mA    3.762mA    8.912mA
25mV      -631.9uA   -432.1uA   -1.07mA
190mV     -4.372mA   -2.969mA   -7.464mA
355mV     -7.378mA   -4.969mA   -12.72mA
520mV     -9.667mA   -6.446mA   -16.87mA
795mV     -11.95mA   -7.796mA   -21.4mA
1.07V     -12.7mA    -8.16mA    -23.29mA
3.6V      -14.81mA   -9.369mA   -27.75mA
[GND_clamp]
|Voltage   I(typ)   I(min)   I(max)
-1.8V     -1.677A    -1.372A    -2.207A
-1.097V   -411.7mA   -430.5mA   -393mA
-1.06V    -351mA     -384.7mA   -309.9mA
-986mV    -235.9mA   -295.9mA   -164.8mA
-949mV    -183mA     -253.4mA   -113.1mA
-912mV    -135mA     -212.5mA   -83.39mA
-838mV    -63.2mA    -137.2mA   -62.73mA
-801mV    -43.97mA   -103.8mA   -56.32mA
-690mV    -21.54mA   -30.09mA   -34.79mA
-579mV    -9.102mA   -5.388mA   -15.4mA
-357mV    -191.3uA   -96.81uA   -298.1uA
1.8V      -12.41nA   0A         -10.91uA
[POWER_clamp]
|Voltage   I(typ)   I(min)   I(max)
-1.8V     23.65mA    14.95mA    43.22mA
-1.419V   17.27mA    10.75mA    32.84mA
-975mV    9.322mA    5.649mA    19.37mA
-864mV    7.265mA    4.408mA    15.69mA
-790mV    5.86mA     3.598mA    12.87mA
-679mV    3.655mA    2.417mA    7.32mA
-605mV    2.107mA    1.665mA    4.016mA
-531mV    854uA      968.7uA    1.658mA
-457mV    251.6uA    402uA      448.6uA
-383mV    77.17uA    103.3uA    115.3uA
-235mV    19.9uA     13.46uA    32.69uA
1.8V      0A         0A         0A
[Ramp]
| variable   typ   min   max
dV/dt_r   0.382/0.383n   0.248/0.439n   0.649/0.316n
dV/dt_f   0.491/0.348n   0.300/0.435n   0.725/0.287n
R_load = 50.000
[Rising Waveform]
R_fixture= 50.000
V_fixture= 0.0
V_fixture_min= 0.0
V_fixture_max= 0.0
|time   V(typ)   V(min)   V(max)
0s        4.637nV    47.96nV    2.735nV
699ps     19.92uV    27.24uV    -21.25mV
1.026ns   -762.3uV   2.285uV    803.1mV
1.322ns   -11.91mV   112.7uV    972.2mV
1.609ns   391mV      -125.2uV   1.027V
1.886ns   532.6mV    -2.337mV   1.049V
2.327ns   595.2mV    -8.292mV   1.063V
2.965ns   622.8mV    341.8mV    1.075V
3.87ns    633.1mV    399.7mV    1.081V
20ns      636.4mV    413.8mV    1.081V
[Rising Waveform]
R_fixture= 50.000
V_fixture= 1.800
V_fixture_min= 1.710
V_fixture_max= 1.890
|time   V(typ)   V(min)   V(max)
0s        981.3mV    1.21V      681.2mV
620ps     981.3mV    1.21V      681.3mV
799ps     981.5mV    1.21V      1.521V
890ps     982.5mV    1.21V      1.743V
1.145ns   996.2mV    1.21V      1.849V
1.454ns   1.632V     1.211V     1.873V
1.914ns   1.778V     1.197V     1.884V
2.376ns   1.791V     1.588V     1.889V
2.855ns   1.796V     1.693V     1.89V
20ns      1.8V       1.71V      1.89V
[Falling Waveform]
R_fixture= 50.000
V_fixture= 1.800
V_fixture_min= 1.710
V_fixture_max= 1.890
|time   V(typ)   V(min)   V(max)
0s        1.8V       1.71V      1.89V
727ps     1.8V       1.71V      1.922V
911ps     1.799V     1.71V      1.237V
1.07ns    1.8V       1.71V      944.4mV
1.385ns   1.821V     1.71V      767.3mV
1.76ns    1.202V     1.71V      715.9mV
2.471ns   1.013V     1.738V     694.3mV
3.055ns   992.9mV    1.322V     683.6mV
3.993ns   983.6mV    1.224V     681.6mV
20ns      981.3mV    1.21V      681.1mV
[Falling Waveform]
R_fixture= 50.000
V_fixture= 0.0
V_fixture_min= 0.0
V_fixture_max= 0.0
|time   V(typ)   V(min)   V(max)
0s        636.4mV    413.8mV    1.081V
667ps     636.5mV    413.8mV    1.072V
898ps     636.2mV    413.8mV    134.6mV
1.286ns   578.3mV    413.8mV    16.25mV
1.565ns   94.87mV    413.7mV    7.21mV
1.914ns   14mV       413.3mV    2.687mV
2.217ns   6.668mV    405.3mV    1.2mV
2.732ns   2.388mV    54.29mV    324uV
3.279ns   804.7uV    6.583mV    78.08uV
20ns      -150.4nV   14.78nV    -539.4nV
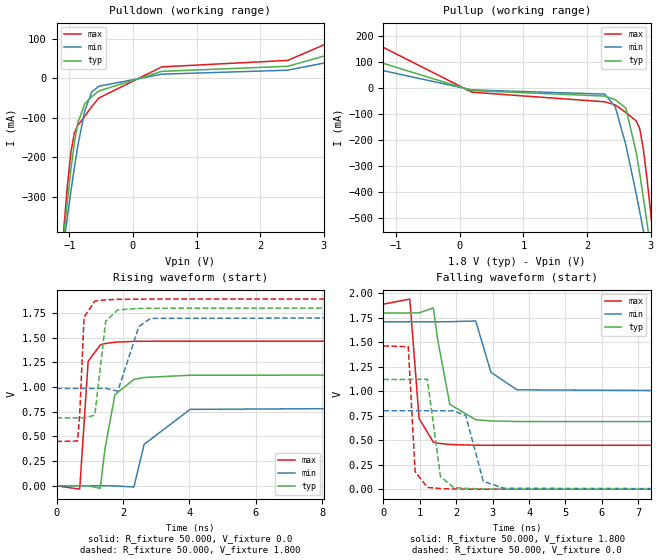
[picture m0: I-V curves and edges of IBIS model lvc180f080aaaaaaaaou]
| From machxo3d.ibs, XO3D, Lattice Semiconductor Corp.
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|   Model lvc180f080aaaaaaaaou
[Model] lvc180f080aaaaaaaaou
Model_type Output
Polarity   Non-Inverting
Enable   Active-High
Vmeas =  0.900V
Cref =  0.0F
Rref =  1.000M
Vref =  0.0V
C_comp   4.200pF   3.800pF   7.500pF
[Temperature Range]   25.000   0.105k   -40.000
[Voltage Range]   1.800V   1.710V   1.890V
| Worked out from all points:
|   slope of the pulldown table from 0 to 0.27 V, typ, clamps not added: 22.7 ohm
|   slope of the pullup table from 0 to 0.27 V, typ, clamps not added: 22.8 ohm
|   rising waveform, R_fixture 50.000, V_fixture 0.0: 20-80 % time 316ps typ, 458ps min, 152ps max; typ from 0 V to 1.12 V
|   rising waveform, R_fixture 50.000, V_fixture 1.800: 20-80 % time 207ps typ, 351ps min, 103ps max; typ from 0.688 V to 1.8 V
|   falling waveform, R_fixture 50.000, V_fixture 1.800: 20-80 % time 291ps typ, 410ps min, 177ps max; typ from 1.8 V to 0.688 V
|   falling waveform, R_fixture 50.000, V_fixture 0.0: 20-80 % time 178ps typ, 306ps min, 101ps max; typ from 1.12 V to 0 V
[Pulldown]
|Voltage   I(typ)   I(min)   I(max)
-1.8V     -1.678A    -1.373A    -2.208A
-1.085V   -398.1mA   -418.6mA   -380.8mA
-1.03V    -311.8mA   -351.7mA   -273.2mA
-975mV    -232.6mA   -287.4mA   -188.9mA
-920mV    -164.8mA   -226.6mA   -138.5mA
-865mV    -112.4mA   -170.7mA   -119.2mA
-755mV    -64.17mA   -81.42mA   -96.06mA
-645mV    -46.16mA   -34.1mA    -71.45mA
-535mV    -32.14mA   -20.1mA    -49.96mA
455mV     17.66mA    10.44mA    28.95mA
2.435V    30.43mA    20.53mA    45.35mA
3.6V      83.36mA    57.69mA    126.2mA
[Pullup]
|Voltage   I(typ)   I(min)   I(max)
-1.8V     141.6mA    100.1mA    232.4mA
190mV     -8.744mA   -5.939mA   -14.93mA
2.28V     -29.88mA   -22.22mA   -51.89mA
2.445V    -43.83mA   -71.95mA   -63.87mA
2.61V     -75.82mA   -217.6mA   -93.14mA
2.775V    -248.3mA   -409mA     -125.8mA
2.83V     -331.8mA   -477.6mA   -157mA
2.885V    -420.5mA   -547.6mA   -233.4mA
2.94V     -512.6mA   -618.9mA   -341.8mA
2.995V    -607.1mA   -691mA     -465.2mA
3.05V     -703.3mA   -763.9mA   -596.3mA
3.6V      -1.707A    -1.515A    -2.022A
[Ramp]
| variable   typ   min   max
dV/dt_r   0.673/0.313n   0.481/0.454n   0.878/0.152n
dV/dt_f   0.667/0.295n   0.435/0.417n   0.865/0.178n
R_load = 50.000
[Rising Waveform]
R_fixture= 50.000
V_fixture= 0.0
V_fixture_min= 0.0
V_fixture_max= 0.0
|time   V(typ)   V(min)   V(max)
0s        3.652nV    38.62nV    2.158nV
699ps     44.57uV    26.96uV    -34.54mV
953ps     -288.4uV   2.052uV    1.259V
1.316ns   -26.64mV   116.8uV    1.425V
1.456ns   365mV      69.53uV    1.439V
1.758ns   922mV      -1.023mV   1.453V
2.331ns   1.076V     -12.85mV   1.462V
2.64ns    1.096V     419.5mV    1.463V
4.026ns   1.119V     773.2mV    1.464V
20ns      1.121V     801mV      1.464V
[Rising Waveform]
R_fixture= 50.000
V_fixture= 1.800
V_fixture_min= 1.710
V_fixture_max= 1.890
|time   V(typ)   V(min)   V(max)
0s        687.7mV    984.9mV    448.1mV
632ps     687.7mV    984.9mV    452.9mV
696ps     687.6mV    984.9mV    703.6mV
830ps     687.9mV    984.9mV    1.707V
1.154ns   713.7mV    984.8mV    1.869V
1.481ns   1.665V     986mV      1.882V
1.846ns   1.781V     958.2mV    1.887V
2.481ns   1.795V     1.612V     1.889V
2.828ns   1.797V     1.694V     1.89V
20ns      1.8V       1.71V      1.89V
[Falling Waveform]
R_fixture= 50.000
V_fixture= 1.800
V_fixture_min= 1.710
V_fixture_max= 1.890
|time   V(typ)   V(min)   V(max)
0s        1.8V       1.71V      1.89V
725ps     1.8V       1.71V      1.942V
980ps     1.801V     1.71V      720.9mV
1.372ns   1.851V     1.71V      480mV
1.49ns    1.528V     1.71V      468.9mV
1.823ns   866.9mV    1.711V     456.6mV
2.535ns   709.1mV    1.718V     449.1mV
2.953ns   697.1mV    1.194V     448.4mV
3.669ns   691.2mV    1.015V     448.1mV
20ns      687.6mV    984.8mV    448mV
[Falling Waveform]
R_fixture= 50.000
V_fixture= 0.0
V_fixture_min= 0.0
V_fixture_max= 0.0
|time   V(typ)   V(min)   V(max)
0s        1.121V     801mV      1.464V
683ps     1.121V     801.1mV    1.455V
871ps     1.121V     801.1mV    180.2mV
1.207ns   1.123V     801mV      18.28mV
1.566ns   129.7mV    801mV      6.295mV
1.929ns   16.51mV    799.8mV    1.964mV
2.261ns   8.085mV    752.8mV    747.4uV
2.743ns   3.04mV     79.5mV     203.7uV
3.315ns   960.7uV    8.573mV    70.21uV
20ns      -417.5nV   -224.1nV   -507.9nV
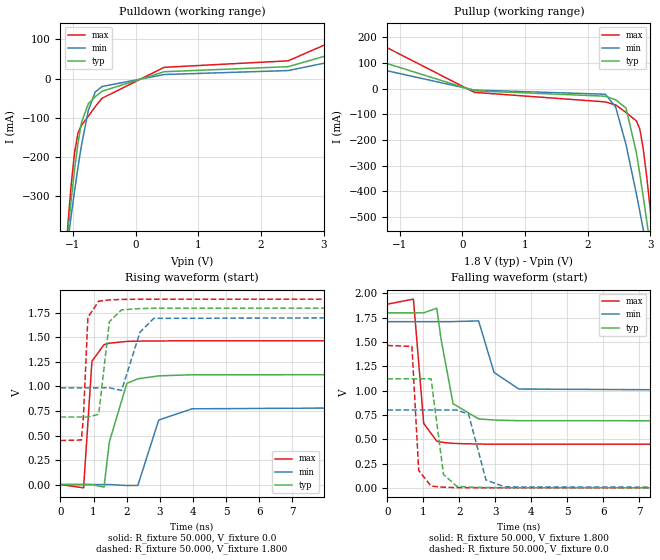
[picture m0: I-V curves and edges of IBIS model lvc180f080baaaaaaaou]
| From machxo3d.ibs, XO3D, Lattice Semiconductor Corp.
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|   Model lvc180f080baaaaaaaou
[Model] lvc180f080baaaaaaaou
Model_type Output
Polarity   Non-Inverting
Enable   Active-High
Vmeas =  0.900V
Cref =  0.0F
Rref =  1.000M
Vref =  0.0V
C_comp   4.200pF   3.800pF   7.500pF
[Temperature Range]   25.000   0.105k   -40.000
[Voltage Range]   1.800V   1.710V   1.890V
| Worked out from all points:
|   slope of the pulldown table from 0 to 0.27 V, typ, clamps not added: 22.7 ohm
|   slope of the pullup table from 0 to 0.27 V, typ, clamps not added: 22.8 ohm
|   rising waveform, R_fixture 50.000, V_fixture 0.0: 20-80 % time 315ps typ, 457ps min, 151ps max; typ from 0.001 V to 1.12 V
|   rising waveform, R_fixture 50.000, V_fixture 1.800: 20-80 % time 207ps typ, 350ps min, 103ps max; typ from 0.689 V to 1.8 V
|   falling waveform, R_fixture 50.000, V_fixture 1.800: 20-80 % time 292ps typ, 398ps min, 177ps max; typ from 1.8 V to 0.689 V
|   falling waveform, R_fixture 50.000, V_fixture 0.0: 20-80 % time 178ps typ, 304ps min, 102ps max; typ from 1.12 V to 0.001 V
[Pulldown]
|Voltage   I(typ)   I(min)   I(max)
-1.8V     -1.678A    -1.373A    -2.208A
-1.085V   -398.1mA   -418.6mA   -380.8mA
-1.03V    -311.8mA   -351.7mA   -273.2mA
-975mV    -232.6mA   -287.4mA   -189mA
-920mV    -164.8mA   -226.6mA   -138.6mA
-865mV    -112.4mA   -170.8mA   -119.3mA
-755mV    -64.19mA   -81.42mA   -96.09mA
-645mV    -46.18mA   -34.11mA   -71.49mA
-535mV    -32.16mA   -20.11mA   -50.01mA
455mV     17.62mA    10.42mA    28.87mA
2.435V    30.47mA    20.58mA    45.4mA
3.6V      84.04mA    58.67mA    126.8mA
[Pullup]
|Voltage   I(typ)   I(min)   I(max)
-1.8V     142.3mA    101mA      233mA
190mV     -8.756mA   -5.946mA   -14.95mA
2.28V     -29.91mA   -22.24mA   -51.96mA
2.445V    -43.84mA   -71.96mA   -63.91mA
2.61V     -75.83mA   -217.6mA   -93.16mA
2.775V    -248.3mA   -409mA     -125.8mA
2.83V     -331.8mA   -477.6mA   -157mA
2.885V    -420.5mA   -547.7mA   -233.4mA
2.94V     -512.7mA   -618.9mA   -341.9mA
2.995V    -607.1mA   -691mA     -465.2mA
3.05V     -703.3mA   -763.9mA   -596.3mA
3.6V      -1.707A    -1.515A    -2.022A
[Ramp]
| variable   typ   min   max
dV/dt_r   0.673/0.312n   0.481/0.454n   0.878/0.151n
dV/dt_f   0.667/0.296n   0.435/0.418n   0.864/0.179n
R_load = 50.000
[Rising Waveform]
R_fixture= 50.000
V_fixture= 0.0
V_fixture_min= 0.0
V_fixture_max= 0.0
|time   V(typ)   V(min)   V(max)
0s        542.4uV    393.2uV    769.5uV
699ps     587uV      419.8uV    -33.31mV
951ps     246.4uV    394.9uV    1.257V
1.316ns   -25.58mV   516.1uV    1.426V
1.477ns   435mV      460.5uV    1.441V
2.006ns   1.032V     -9.477mV   1.459V
2.337ns   1.078V     -8.378mV   1.462V
2.968ns   1.108V     657.7mV    1.464V
3.973ns   1.119V     772.3mV    1.465V
20ns      1.122V     801.9mV    1.465V
[Rising Waveform]
R_fixture= 50.000
V_fixture= 1.800
V_fixture_min= 1.710
V_fixture_max= 1.890
|time   V(typ)   V(min)   V(max)
0s        688.8mV    985.7mV    449.4mV
632ps     688.9mV    985.7mV    454.3mV
696ps     688.8mV    985.7mV    705.7mV
829ps     689.1mV    985.7mV    1.705V
1.155ns   716.5mV    985.6mV    1.869V
1.477ns   1.66V      986.8mV    1.882V
1.846ns   1.781V     959mV      1.887V
2.403ns   1.794V     1.554V     1.889V
2.821ns   1.797V     1.694V     1.89V
20ns      1.8V       1.71V      1.89V
[Falling Waveform]
R_fixture= 50.000
V_fixture= 1.800
V_fixture_min= 1.710
V_fixture_max= 1.890
|time   V(typ)   V(min)   V(max)
0s        1.8V       1.71V      1.89V
725ps     1.8V       1.71V      1.942V
1.011ns   1.801V     1.71V      662.6mV
1.374ns   1.849V     1.71V      481.2mV
1.493ns   1.528V     1.71V      470.1mV
1.827ns   865.7mV    1.711V     457.8mV
2.535ns   710.3mV    1.718V     450.9mV
2.964ns   698.1mV    1.188V     449.9mV
3.654ns   691.4mV    1.017V     449.5mV
20ns      688.9mV    985.6mV    449.3mV
[Falling Waveform]
R_fixture= 50.000
V_fixture= 0.0
V_fixture_min= 0.0
V_fixture_max= 0.0
|time   V(typ)   V(min)   V(max)
0s        1.122V     801.9mV    1.465V
683ps     1.122V     801.9mV    1.456V
872ps     1.122V     801.9mV    179.2mV
1.215ns   1.123V     801.9mV    18.53mV
1.561ns   137.4mV    801.9mV    7.058mV
1.927ns   17.19mV    800.7mV    2.713mV
2.256ns   8.33mV     759mV      1.506mV
2.741ns   3.791mV    81.16mV    967uV
3.265ns   1.607mV    9.95mV     836.6uV
20ns      542uV      393.1uV    768.9uV
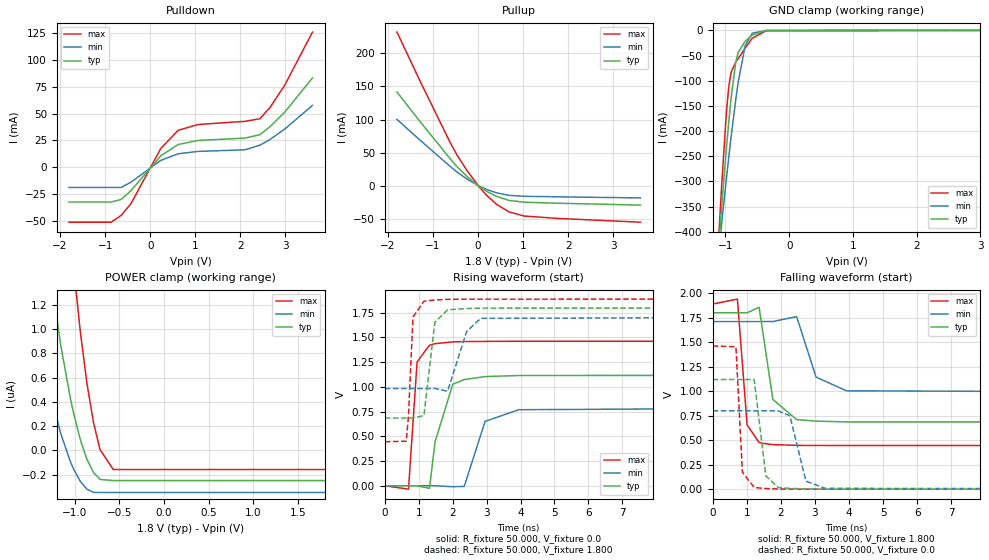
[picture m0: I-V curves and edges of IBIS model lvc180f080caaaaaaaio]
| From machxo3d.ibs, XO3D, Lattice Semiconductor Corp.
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|   Model lvc180f080caaaaaaaio
[Model] lvc180f080caaaaaaaio
Model_type I/O
Polarity   Non-Inverting
Enable   Active-Low
Vinl =  0.630V
Vinh =  1.170V
Vmeas =  0.900V
Cref =  0.0F
Rref =  1.000M
Vref =  0.0V
C_comp   4.200pF   3.800pF   7.500pF
[Temperature Range]   25.000   0.105k   -40.000
[Voltage Range]   1.800V   1.710V   1.890V
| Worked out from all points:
|   slope of the pulldown table from 0 to 0.27 V, typ, clamps not added: 22.7 ohm
|   slope of the pullup table from 0 to 0.27 V, typ, clamps not added: 22.8 ohm
|   GND clamp passes 1 mA (typ) near -0.44 V on its own axis
|   rising waveform, R_fixture 50.000, V_fixture 0.0: 20-80 % time 315ps typ, 454ps min, 152ps max; typ from 0 V to 1.12 V
|   rising waveform, R_fixture 50.000, V_fixture 1.800: 20-80 % time 205ps typ, 349ps min, 103ps max; typ from 0.685 V to 1.8 V
|   falling waveform, R_fixture 50.000, V_fixture 1.800: 20-80 % time 288ps typ, 419ps min, 175ps max; typ from 1.8 V to 0.685 V
|   falling waveform, R_fixture 50.000, V_fixture 0.0: 20-80 % time 178ps typ, 305ps min, 101ps max; typ from 1.12 V to 0 V
[Pulldown]
|Voltage   I(typ)   I(min)   I(max)
-1.8V     -32.67mA   -18.98mA   -51.52mA
-865mV    -32.67mA   -18.98mA   -51.52mA
-645mV    -30.22mA   -18.98mA   -45.17mA
-425mV    -21.97mA   -14.07mA   -34.06mA
235mV     10.62mA    6.321mA    17.45mA
620mV     21.15mA    12.46mA    34.42mA
1.06V     24.95mA    14.7mA     39.84mA
2.105V    27.14mA    16.2mA     42.84mA
2.435V    30.4mA     20.52mA    45.25mA
2.655V    37.72mA    25.74mA    55.67mA
2.985V    51.47mA    35.63mA    76.67mA
3.6V      83.41mA    57.72mA    126.3mA
[Pullup]
|Voltage   I(typ)   I(min)   I(max)
-1.8V     141.6mA    100.2mA    232.4mA
-1.295V   97.55mA    69.14mA    159.2mA
-635mV    41.87mA    29.84mA    67.2mA
-470mV    28.69mA    20.63mA    46.35mA
-250mV    14.07mA    9.891mA    23.18mA
25mV      -1.264mA   -864.3uA   -2.139mA
190mV     -8.744mA   -5.939mA   -14.93mA
410mV     -16.44mA   -11.04mA   -28.45mA
685mV     -22.52mA   -14.83mA   -39.88mA
1.015V    -25.23mA   -16.24mA   -46.13mA
1.785V    -26.82mA   -17.12mA   -49.85mA
3.6V      -29.62mA   -18.74mA   -55.5mA
[GND_clamp]
|Voltage   I(typ)   I(min)   I(max)
-1.8V     -1.677A    -1.372A    -2.207A
-1.097V   -411.7mA   -430.5mA   -393mA
-1.06V    -351mA     -384.7mA   -309.9mA
-986mV    -235.9mA   -295.9mA   -164.8mA
-949mV    -183mA     -253.4mA   -113.1mA
-912mV    -135mA     -212.5mA   -83.39mA
-838mV    -63.2mA    -137.2mA   -62.73mA
-801mV    -43.97mA   -103.8mA   -56.32mA
-690mV    -21.54mA   -30.09mA   -34.79mA
-579mV    -9.102mA   -5.388mA   -15.4mA
-357mV    -191.3uA   -96.81uA   -298.1uA
3.6V      109.7uA    43.11uA    257.2uA
[POWER_clamp]
|Voltage   I(typ)   I(min)   I(max)
-1.8V     5.719uA    2.929uA    14.07uA
-1.567V   3.495uA    1.63uA     8.906uA
-1.308V   1.654uA    574.5nA    4.658uA
-1.16V    879.1nA    145.5nA    2.867uA
-1.049V   428.7nA    -92.09nA   1.807uA
-1.012V   303.4nA    -154.9nA   1.506uA
-938mV    90.15nA    -254.7nA   980.1nA
-864mV    -72.35nA   -318.6nA   555.1nA
-790mV    -182.4nA   -345.7nA   230.3nA
-716mV    -238.9nA   -346.3nA   6nA
-568mV    -248.1nA   -346.3nA   -157.2nA
1.8V      -248.1nA   -346.3nA   -157.2nA
[Ramp]
| variable   typ   min   max
dV/dt_r   0.671/0.313n   0.480/0.454n   0.876/0.152n
dV/dt_f   0.668/0.294n   0.436/0.417n   0.865/0.177n
R_load = 50.000
[Rising Waveform]
R_fixture= 50.000
V_fixture= 0.0
V_fixture_min= 0.0
V_fixture_max= 0.0
|time   V(typ)   V(min)   V(max)
0s        3.523nV    38.23nV    1.999nV
699ps     44.57uV    26.91uV    -34.43mV
951ps     -294.4uV   1.913uV    1.252V
1.317ns   -25.54mV   117.8uV    1.421V
1.48ns    442.8mV    68.37uV    1.437V
2.003ns   1.027V     -9.681mV   1.455V
2.341ns   1.074V     -6.407mV   1.458V
2.955ns   1.104V     651.1mV    1.46V
3.945ns   1.115V     768.9mV    1.461V
20ns      1.118V     799.4mV    1.461V
[Rising Waveform]
R_fixture= 50.000
V_fixture= 1.800
V_fixture_min= 1.710
V_fixture_max= 1.890
|time   V(typ)   V(min)   V(max)
0s        684.9mV    983.3mV    445.4mV
632ps     684.9mV    983.3mV    450.1mV
696ps     684.9mV    983.3mV    699.3mV
831ps     685.1mV    983.3mV    1.706V
1.153ns   709.3mV    983.2mV    1.866V
1.474ns   1.653V     984.5mV    1.879V
1.85ns    1.779V     956.4mV    1.885V
2.413ns   1.792V     1.561V     1.887V
2.826ns   1.796V     1.693V     1.887V
20ns      1.799V     1.709V     1.888V
[Falling Waveform]
R_fixture= 50.000
V_fixture= 1.800
V_fixture_min= 1.710
V_fixture_max= 1.890
|time   V(typ)   V(min)   V(max)
0s        1.799V     1.709V     1.888V
725ps     1.799V     1.709V     1.939V
1.01ns    1.799V     1.709V     655.1mV
1.361ns   1.855V     1.709V     476.8mV
1.463ns   1.619V     1.709V     467.7mV
1.766ns   915mV      1.71V      454.5mV
2.463ns   709.6mV    1.76V      446.7mV
3.033ns   694.2mV    1.143V     445.7mV
3.928ns   686.1mV    1.003V     445.5mV
20ns      684.9mV    983.3mV    445.4mV
[Falling Waveform]
R_fixture= 50.000
V_fixture= 0.0
V_fixture_min= 0.0
V_fixture_max= 0.0
|time   V(typ)   V(min)   V(max)
0s        1.118V     799.4mV    1.461V
682ps     1.119V     799.5mV    1.452V
872ps     1.118V     799.5mV    173.7mV
1.217ns   1.119V     799.5mV    17.26mV
1.56ns    135.7mV    799.4mV    6.325mV
1.922ns   16.57mV    798.2mV    2mV
2.263ns   7.464mV    749mV      769.2uV
2.736ns   3.057mV    82.38mV    209.4uV
3.292ns   958.7uV    8.955mV    73.29uV
20ns      -386.9nV   -84.68nV   -221.5nV
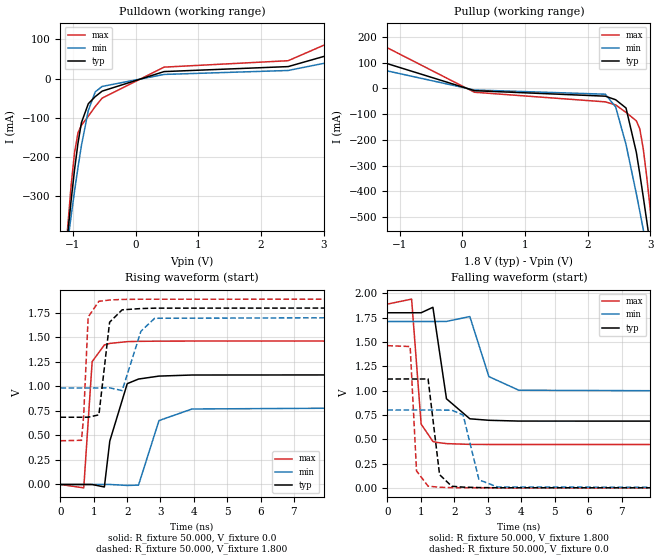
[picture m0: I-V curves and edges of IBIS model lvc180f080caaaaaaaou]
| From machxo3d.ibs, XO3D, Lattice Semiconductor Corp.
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|   Model lvc180f080caaaaaaaou
[Model] lvc180f080caaaaaaaou
Model_type Output
Polarity   Non-Inverting
Enable   Active-High
Vmeas =  0.900V
Cref =  0.0F
Rref =  1.000M
Vref =  0.0V
C_comp   4.200pF   3.800pF   7.500pF
[Temperature Range]   25.000   0.105k   -40.000
[Voltage Range]   1.800V   1.710V   1.890V
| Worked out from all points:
|   slope of the pulldown table from 0 to 0.27 V, typ, clamps not added: 22.6 ohm
|   slope of the pullup table from 0 to 0.27 V, typ, clamps not added: 22.8 ohm
|   rising waveform, R_fixture 50.000, V_fixture 0.0: 20-80 % time 315ps typ, 454ps min, 152ps max; typ from 0 V to 1.12 V
|   rising waveform, R_fixture 50.000, V_fixture 1.800: 20-80 % time 205ps typ, 349ps min, 103ps max; typ from 0.685 V to 1.8 V
|   falling waveform, R_fixture 50.000, V_fixture 1.800: 20-80 % time 288ps typ, 419ps min, 175ps max; typ from 1.8 V to 0.685 V
|   falling waveform, R_fixture 50.000, V_fixture 0.0: 20-80 % time 178ps typ, 305ps min, 101ps max; typ from 1.12 V to 0 V
[Pulldown]
|Voltage   I(typ)   I(min)   I(max)
-1.8V     -1.678A    -1.373A    -2.208A
-1.085V   -398.1mA   -418.6mA   -380.8mA
-1.03V    -311.9mA   -351.7mA   -273.3mA
-975mV    -232.6mA   -287.4mA   -189mA
-920mV    -164.8mA   -226.7mA   -138.6mA
-865mV    -112.5mA   -170.8mA   -119.3mA
-755mV    -64.22mA   -81.44mA   -96.13mA
-645mV    -46.21mA   -34.14mA   -71.53mA
-535mV    -32.2mA    -20.15mA   -50.06mA
455mV     17.74mA    10.47mA    29.12mA
2.435V    30.5mA     20.56mA    45.5mA
3.6V      83.52mA    57.77mA    126.5mA
[Pullup]
|Voltage   I(typ)   I(min)   I(max)
-1.8V     141.8mA    100.2mA    232.7mA
190mV     -8.643mA   -5.902mA   -14.69mA
2.28V     -29.95mA   -22.26mA   -52.02mA
2.445V    -43.86mA   -71.97mA   -63.95mA
2.61V     -75.85mA   -217.6mA   -93.19mA
2.775V    -248.3mA   -409mA     -125.8mA
2.83V     -331.8mA   -477.6mA   -157mA
2.885V    -420.5mA   -547.7mA   -233.5mA
2.94V     -512.7mA   -618.9mA   -341.9mA
2.995V    -607.1mA   -691mA     -465.3mA
3.05V     -703.3mA   -763.9mA   -596.3mA
3.6V      -1.707A    -1.515A    -2.022A
[Ramp]
| variable   typ   min   max
dV/dt_r   0.671/0.313n   0.480/0.454n   0.876/0.152n
dV/dt_f   0.668/0.294n   0.436/0.417n   0.865/0.177n
R_load = 50.000
[Rising Waveform]
R_fixture= 50.000
V_fixture= 0.0
V_fixture_min= 0.0
V_fixture_max= 0.0
|time   V(typ)   V(min)   V(max)
0s        3.523nV    38.23nV    1.999nV
699ps     44.57uV    26.91uV    -34.43mV
951ps     -294.4uV   1.913uV    1.252V
1.317ns   -25.54mV   117.8uV    1.421V
1.48ns    442.8mV    68.37uV    1.437V
2.003ns   1.027V     -9.681mV   1.455V
2.341ns   1.074V     -6.407mV   1.458V
2.955ns   1.104V     651.1mV    1.46V
3.945ns   1.115V     768.9mV    1.461V
20ns      1.118V     799.4mV    1.461V
[Rising Waveform]
R_fixture= 50.000
V_fixture= 1.800
V_fixture_min= 1.710
V_fixture_max= 1.890
|time   V(typ)   V(min)   V(max)
0s        684.9mV    983.3mV    445.4mV
632ps     684.9mV    983.3mV    450.1mV
696ps     684.9mV    983.3mV    699.3mV
831ps     685.1mV    983.3mV    1.706V
1.153ns   709.3mV    983.2mV    1.866V
1.474ns   1.653V     984.5mV    1.879V
1.85ns    1.779V     956.4mV    1.885V
2.413ns   1.792V     1.561V     1.887V
2.826ns   1.796V     1.693V     1.887V
20ns      1.799V     1.709V     1.888V
[Falling Waveform]
R_fixture= 50.000
V_fixture= 1.800
V_fixture_min= 1.710
V_fixture_max= 1.890
|time   V(typ)   V(min)   V(max)
0s        1.799V     1.709V     1.888V
725ps     1.799V     1.709V     1.939V
1.01ns    1.799V     1.709V     655.1mV
1.361ns   1.855V     1.709V     476.8mV
1.463ns   1.619V     1.709V     467.7mV
1.766ns   915mV      1.71V      454.5mV
2.463ns   709.6mV    1.76V      446.7mV
3.033ns   694.2mV    1.143V     445.7mV
3.928ns   686.1mV    1.003V     445.5mV
20ns      684.9mV    983.3mV    445.4mV
[Falling Waveform]
R_fixture= 50.000
V_fixture= 0.0
V_fixture_min= 0.0
V_fixture_max= 0.0
|time   V(typ)   V(min)   V(max)
0s        1.118V     799.4mV    1.461V
682ps     1.119V     799.5mV    1.452V
872ps     1.118V     799.5mV    173.7mV
1.217ns   1.119V     799.5mV    17.26mV
1.56ns    135.7mV    799.4mV    6.325mV
1.922ns   16.57mV    798.2mV    2mV
2.263ns   7.464mV    749mV      769.2uV
2.736ns   3.057mV    82.38mV    209.4uV
3.292ns   958.7uV    8.955mV    73.29uV
20ns      -386.9nV   -84.68nV   -221.5nV
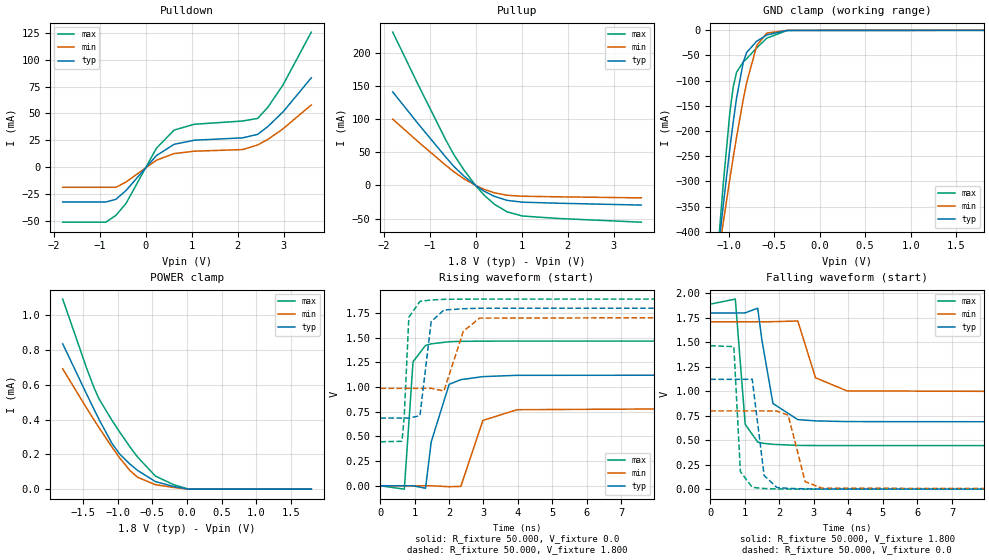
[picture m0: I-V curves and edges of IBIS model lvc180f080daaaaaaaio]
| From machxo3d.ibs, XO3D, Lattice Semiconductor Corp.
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|   Model lvc180f080daaaaaaaio
[Model] lvc180f080daaaaaaaio
Model_type I/O
Polarity   Non-Inverting
Enable   Active-Low
Vinl =  0.630V
Vinh =  1.170V
Vmeas =  0.900V
Cref =  0.0F
Rref =  1.000M
Vref =  0.0V
C_comp   4.200pF   3.800pF   7.500pF
[Temperature Range]   25.000   0.105k   -40.000
[Voltage Range]   1.800V   1.710V   1.890V
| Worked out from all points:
|   slope of the pulldown table from 0 to 0.27 V, typ, clamps not added: 22.7 ohm
|   slope of the pullup table from 0 to 0.27 V, typ, clamps not added: 22.8 ohm
|   GND clamp passes 1 mA (typ) near -0.44 V on its own axis
|   rising waveform, R_fixture 50.000, V_fixture 0.0: 20-80 % time 317ps typ, 456ps min, 153ps max; typ from 0 V to 1.12 V
|   rising waveform, R_fixture 50.000, V_fixture 1.800: 20-80 % time 206ps typ, 348ps min, 103ps max; typ from 0.685 V to 1.8 V
|   falling waveform, R_fixture 50.000, V_fixture 1.800: 20-80 % time 295ps typ, 398ps min, 178ps max; typ from 1.8 V to 0.685 V
|   falling waveform, R_fixture 50.000, V_fixture 0.0: 20-80 % time 178ps typ, 303ps min, 102ps max; typ from 1.12 V to 0 V
[Pulldown]
|Voltage   I(typ)   I(min)   I(max)
-1.8V     -32.67mA   -18.98mA   -51.52mA
-865mV    -32.67mA   -18.98mA   -51.52mA
-645mV    -30.22mA   -18.98mA   -45.17mA
-425mV    -21.97mA   -14.07mA   -34.06mA
235mV     10.62mA    6.321mA    17.45mA
620mV     21.15mA    12.46mA    34.42mA
1.06V     24.95mA    14.7mA     39.84mA
2.105V    27.14mA    16.2mA     42.84mA
2.435V    30.39mA    20.51mA    45.29mA
2.655V    37.67mA    25.68mA    55.62mA
2.985V    51.32mA    35.55mA    76.49mA
3.6V      83.2mA     57.91mA    125.8mA
[Pullup]
|Voltage   I(typ)   I(min)   I(max)
-1.8V     141.5mA    100.3mA    231.9mA
-1.24V    92.66mA    65.69mA    151.3mA
-635mV    41.85mA    29.84mA    67.18mA
-470mV    28.7mA     20.63mA    46.39mA
-250mV    14.07mA    9.891mA    23.18mA
25mV      -1.264mA   -864.3uA   -2.139mA
190mV     -8.744mA   -5.939mA   -14.93mA
410mV     -16.44mA   -11.04mA   -28.45mA
685mV     -22.52mA   -14.83mA   -39.88mA
1.015V    -25.23mA   -16.24mA   -46.13mA
1.785V    -26.82mA   -17.12mA   -49.85mA
3.6V      -29.62mA   -18.74mA   -55.5mA
[GND_clamp]
|Voltage   I(typ)   I(min)   I(max)
-1.8V     -1.677A    -1.372A    -2.207A
-1.097V   -411.7mA   -430.5mA   -393mA
-1.06V    -351mA     -384.7mA   -309.9mA
-986mV    -235.9mA   -295.9mA   -164.8mA
-949mV    -183mA     -253.4mA   -113.1mA
-912mV    -135mA     -212.5mA   -83.39mA
-838mV    -63.2mA    -137.2mA   -62.73mA
-801mV    -43.97mA   -103.8mA   -56.32mA
-690mV    -21.54mA   -30.09mA   -34.79mA
-579mV    -9.102mA   -5.388mA   -15.4mA
-357mV    -191.3uA   -96.81uA   -298.1uA
1.8V      -12.41nA   0A         -10.91uA
[POWER_clamp]
|Voltage   I(typ)   I(min)   I(max)
-1.8V     836.1uA    692.5uA    1.094mA
-1.456V   549uA      467.8uA    698.7uA
-1.345V   458uA      397.8uA    582.4uA
-1.271V   398.7uA    352uA      517.3uA
-1.086V   262.9uA    241.7uA    395.6uA
-975mV    202uA      179.8uA    328.7uA
-827mV    144.5uA    107.4uA    243.8uA
-716mV    108uA      68.49uA    184.9uA
-457mV    43.42uA    25.76uA    75.17uA
-198mV    15.77uA    10.09uA    26.67uA
24mV      0A         0A         0A
1.8V      0A         0A         0A
[Ramp]
| variable   typ   min   max
dV/dt_r   0.673/0.316n   0.480/0.454n   0.879/0.153n
dV/dt_f   0.669/0.299n   0.435/0.418n   0.867/0.180n
R_load = 50.000
[Rising Waveform]
R_fixture= 50.000
V_fixture= 0.0
V_fixture_min= 0.0
V_fixture_max= 0.0
|time   V(typ)   V(min)   V(max)
0s        3.523nV    38.23nV    1.999nV
699ps     44.57uV    26.89uV    -34.43mV
953ps     -290.2uV   1.905uV    1.256V
1.317ns   -25.54mV   117.8uV    1.421V
1.48ns    442.8mV    68.37uV    1.437V
2.003ns   1.027V     -9.681mV   1.458V
2.341ns   1.074V     -6.407mV   1.462V
2.985ns   1.105V     661.6mV    1.464V
3.976ns   1.118V     770mV      1.465V
20ns      1.122V     799.4mV    1.465V
[Rising Waveform]
R_fixture= 50.000
V_fixture= 1.800
V_fixture_min= 1.710
V_fixture_max= 1.890
|time   V(typ)   V(min)   V(max)
0s        684.9mV    985.7mV    445.4mV
632ps     684.9mV    985.7mV    450.1mV
696ps     684.9mV    985.7mV    699.3mV
831ps     685.1mV    985.7mV    1.706V
1.153ns   709.3mV    985.6mV    1.866V
1.48ns    1.662V     986.8mV    1.881V
1.85ns    1.779V     958.8mV    1.887V
2.415ns   1.792V     1.564V     1.889V
2.887ns   1.797V     1.697V     1.89V
20ns      1.8V       1.71V      1.89V
[Falling Waveform]
R_fixture= 50.000
V_fixture= 1.800
V_fixture_min= 1.710
V_fixture_max= 1.890
|time   V(typ)   V(min)   V(max)
0s        1.8V       1.71V      1.89V
725ps     1.8V       1.71V      1.942V
1.011ns   1.801V     1.71V      662.6mV
1.374ns   1.849V     1.71V      481.2mV
1.493ns   1.528V     1.71V      470.1mV
1.815ns   875.1mV    1.711V     458mV
2.535ns   710.3mV    1.718V     446.9mV
3.048ns   697.7mV    1.138V     445.8mV
3.96ns    690.3mV    1.004V     445.4mV
20ns      684.8mV    985.6mV    445.4mV
[Falling Waveform]
R_fixture= 50.000
V_fixture= 0.0
V_fixture_min= 0.0
V_fixture_max= 0.0
|time   V(typ)   V(min)   V(max)
0s        1.122V     799.4mV    1.465V
683ps     1.122V     799.5mV    1.456V
872ps     1.122V     799.5mV    179.2mV
1.215ns   1.123V     799.5mV    18.53mV
1.559ns   140.2mV    799.4mV    6.386mV
1.927ns   17.19mV    798.2mV    2.213mV
2.257ns   8.33mV     755.5mV    902.4uV
2.748ns   3.271mV    76.29mV    280.6uV
3.241ns   1.4mV      9.957mV    112uV
20ns      -31.08nV   -84.68nV   -195.9nV
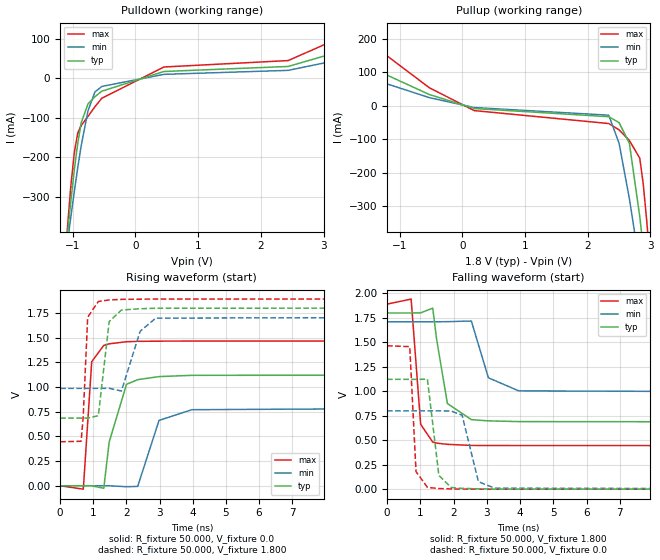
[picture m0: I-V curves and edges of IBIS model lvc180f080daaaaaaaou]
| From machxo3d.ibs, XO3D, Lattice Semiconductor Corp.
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|   Model lvc180f080daaaaaaaou
[Model] lvc180f080daaaaaaaou
Model_type Output
Polarity   Non-Inverting
Enable   Active-High
Vmeas =  0.900V
Cref =  0.0F
Rref =  1.000M
Vref =  0.0V
C_comp   4.200pF   3.800pF   7.500pF
[Temperature Range]   25.000   0.105k   -40.000
[Voltage Range]   1.800V   1.710V   1.890V
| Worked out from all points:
|   slope of the pulldown table from 0 to 0.27 V, typ, clamps not added: 22.6 ohm
|   slope of the pullup table from 0 to 0.27 V, typ, clamps not added: 22.8 ohm
|   rising waveform, R_fixture 50.000, V_fixture 0.0: 20-80 % time 317ps typ, 456ps min, 153ps max; typ from 0 V to 1.12 V
|   rising waveform, R_fixture 50.000, V_fixture 1.800: 20-80 % time 206ps typ, 348ps min, 103ps max; typ from 0.685 V to 1.8 V
|   falling waveform, R_fixture 50.000, V_fixture 1.800: 20-80 % time 295ps typ, 398ps min, 178ps max; typ from 1.8 V to 0.685 V
|   falling waveform, R_fixture 50.000, V_fixture 0.0: 20-80 % time 178ps typ, 303ps min, 102ps max; typ from 1.12 V to 0 V
[Pulldown]
|Voltage   I(typ)   I(min)   I(max)
-1.8V     -1.678A    -1.373A    -2.208A
-1.085V   -398.1mA   -418.6mA   -380.8mA
-1.03V    -311.9mA   -351.7mA   -273.3mA
-975mV    -232.6mA   -287.4mA   -189mA
-920mV    -164.8mA   -226.7mA   -138.6mA
-865mV    -112.5mA   -170.8mA   -119.3mA
-755mV    -64.22mA   -81.44mA   -96.13mA
-645mV    -46.21mA   -34.14mA   -71.53mA
-535mV    -32.2mA    -20.15mA   -50.06mA
455mV     17.74mA    10.47mA    29.12mA
2.435V    30.47mA    20.58mA    45.4mA
3.6V      84.04mA    58.67mA    126.8mA
[Pullup]
|Voltage   I(typ)   I(min)   I(max)
-1.8V     142.3mA    101mA      233mA
-525mV    32.9mA     23.68mA    53.01mA
190mV     -8.756mA   -5.946mA   -14.95mA
2.335V    -33.18mA   -28.7mA    -53.59mA
2.5V      -50.86mA   -112.4mA   -72.45mA
2.665V    -112.9mA   -278.2mA   -104.2mA
2.83V     -331.8mA   -477.6mA   -157mA
2.885V    -420.5mA   -547.7mA   -233.5mA
2.94V     -512.7mA   -618.9mA   -341.9mA
2.995V    -607.1mA   -691mA     -465.3mA
3.05V     -703.3mA   -763.9mA   -596.3mA
3.6V      -1.707A    -1.515A    -2.022A
[Ramp]
| variable   typ   min   max
dV/dt_r   0.673/0.316n   0.480/0.454n   0.879/0.153n
dV/dt_f   0.669/0.299n   0.435/0.418n   0.867/0.180n
R_load = 50.000
[Rising Waveform]
R_fixture= 50.000
V_fixture= 0.0
V_fixture_min= 0.0
V_fixture_max= 0.0
|time   V(typ)   V(min)   V(max)
0s        3.523nV    38.23nV    1.999nV
699ps     44.57uV    26.89uV    -34.43mV
953ps     -290.2uV   1.905uV    1.256V
1.317ns   -25.54mV   117.8uV    1.421V
1.48ns    442.8mV    68.37uV    1.437V
2.003ns   1.027V     -9.681mV   1.458V
2.341ns   1.074V     -6.407mV   1.462V
2.985ns   1.105V     661.6mV    1.464V
3.976ns   1.118V     770mV      1.465V
20ns      1.122V     799.4mV    1.465V
[Rising Waveform]
R_fixture= 50.000
V_fixture= 1.800
V_fixture_min= 1.710
V_fixture_max= 1.890
|time   V(typ)   V(min)   V(max)
0s        684.9mV    985.7mV    445.4mV
632ps     684.9mV    985.7mV    450.1mV
696ps     684.9mV    985.7mV    699.3mV
831ps     685.1mV    985.7mV    1.706V
1.153ns   709.3mV    985.6mV    1.866V
1.48ns    1.662V     986.8mV    1.881V
1.85ns    1.779V     958.8mV    1.887V
2.415ns   1.792V     1.564V     1.889V
2.887ns   1.797V     1.697V     1.89V
20ns      1.8V       1.71V      1.89V
[Falling Waveform]
R_fixture= 50.000
V_fixture= 1.800
V_fixture_min= 1.710
V_fixture_max= 1.890
|time   V(typ)   V(min)   V(max)
0s        1.8V       1.71V      1.89V
725ps     1.8V       1.71V      1.942V
1.011ns   1.801V     1.71V      662.6mV
1.374ns   1.849V     1.71V      481.2mV
1.493ns   1.528V     1.71V      470.1mV
1.815ns   875.1mV    1.711V     458mV
2.535ns   710.3mV    1.718V     446.9mV
3.048ns   697.7mV    1.138V     445.8mV
3.96ns    690.3mV    1.004V     445.4mV
20ns      684.8mV    985.6mV    445.4mV
[Falling Waveform]
R_fixture= 50.000
V_fixture= 0.0
V_fixture_min= 0.0
V_fixture_max= 0.0
|time   V(typ)   V(min)   V(max)
0s        1.122V     799.4mV    1.465V
683ps     1.122V     799.5mV    1.456V
872ps     1.122V     799.5mV    179.2mV
1.215ns   1.123V     799.5mV    18.53mV
1.559ns   140.2mV    799.4mV    6.386mV
1.927ns   17.19mV    798.2mV    2.213mV
2.257ns   8.33mV     755.5mV    902.4uV
2.748ns   3.271mV    76.29mV    280.6uV
3.241ns   1.4mV      9.957mV    112uV
20ns      -31.08nV   -84.68nV   -195.9nV
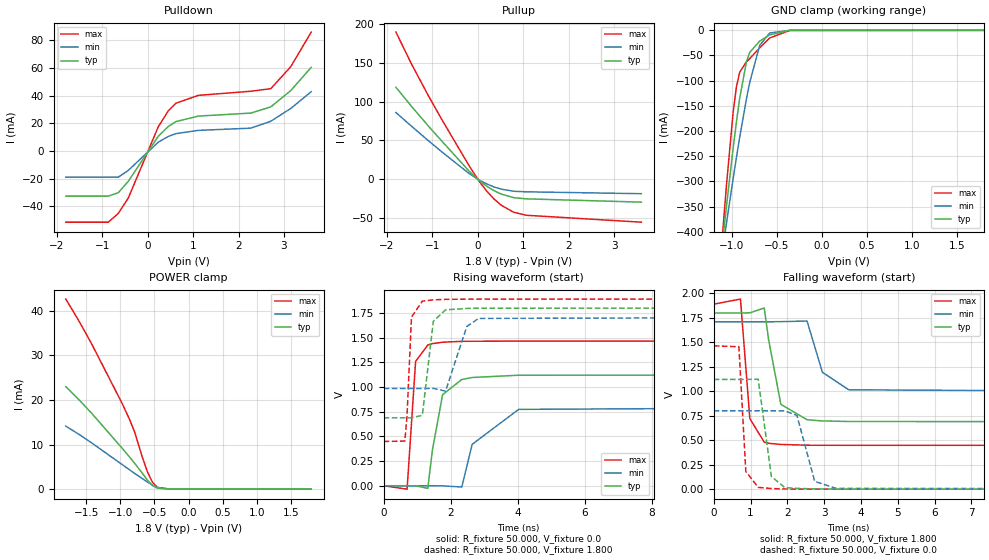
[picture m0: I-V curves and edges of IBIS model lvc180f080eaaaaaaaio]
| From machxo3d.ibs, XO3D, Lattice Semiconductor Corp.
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|   Model lvc180f080eaaaaaaaio
[Model] lvc180f080eaaaaaaaio
Model_type I/O
Polarity   Non-Inverting
Enable   Active-Low
Vinl =  0.630V
Vinh =  1.170V
Vmeas =  0.900V
Cref =  0.0F
Rref =  1.000M
Vref =  0.0V
C_comp   4.200pF   3.800pF   7.500pF
[Temperature Range]   25.000   0.105k   -40.000
[Voltage Range]   1.800V   1.710V   1.890V
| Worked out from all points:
|   slope of the pulldown table from 0 to 0.27 V, typ, clamps not added: 22.7 ohm
|   slope of the pullup table from 0 to 0.27 V, typ, clamps not added: 22.8 ohm
|   GND clamp passes 1 mA (typ) near -0.44 V on its own axis
|   POWER clamp passes 1 mA (typ) near -0.54 V on its own axis
|   rising waveform, R_fixture 50.000, V_fixture 0.0: 20-80 % time 316ps typ, 458ps min, 152ps max; typ from 0 V to 1.12 V
|   rising waveform, R_fixture 50.000, V_fixture 1.800: 20-80 % time 207ps typ, 351ps min, 103ps max; typ from 0.688 V to 1.8 V
|   falling waveform, R_fixture 50.000, V_fixture 1.800: 20-80 % time 291ps typ, 410ps min, 177ps max; typ from 1.8 V to 0.688 V
|   falling waveform, R_fixture 50.000, V_fixture 0.0: 20-80 % time 178ps typ, 306ps min, 101ps max; typ from 1.12 V to 0 V
[Pulldown]
|Voltage   I(typ)   I(min)   I(max)
-1.8V     -32.67mA   -18.98mA   -51.52mA
-865mV    -32.67mA   -18.98mA   -51.52mA
-645mV    -30.22mA   -18.98mA   -45.17mA
-425mV    -21.97mA   -14.07mA   -34.06mA
235mV     10.62mA    6.321mA    17.45mA
455mV     17.66mA    10.44mA    28.95mA
620mV     21.15mA    12.46mA    34.42mA
1.115V    25.16mA    14.83mA    40.14mA
2.27V     27.33mA    16.45mA    43.11mA
2.71V     31.8mA     21.43mA    44.97mA
3.15V     43.59mA    30.69mA    60.87mA
3.6V      60.4mA     42.78mA    85.87mA
[Pullup]
|Voltage   I(typ)   I(min)   I(max)
-1.8V     118.6mA    86.03mA    189.8mA
-1.46V    94.14mA    68.5mA     148.9mA
-1.075V   67.84mA    49.1mA     106.5mA
-800mV    49.79mA    35.74mA    77.94mA
-195mV    10.76mA    7.525mA    17.82mA
25mV      -1.264mA   -864.3uA   -2.139mA
190mV     -8.744mA   -5.939mA   -14.93mA
355mV     -14.76mA   -9.939mA   -25.44mA
520mV     -19.33mA   -12.89mA   -33.74mA
795mV     -23.9mA    -15.59mA   -42.8mA
1.07V     -25.4mA    -16.32mA   -46.58mA
3.6V      -29.62mA   -18.74mA   -55.51mA
[GND_clamp]
|Voltage   I(typ)   I(min)   I(max)
-1.8V     -1.677A    -1.372A    -2.207A
-1.097V   -411.6mA   -430.5mA   -392.9mA
-1.06V    -351mA     -384.7mA   -309.8mA
-986mV    -235.9mA   -295.9mA   -164.7mA
-949mV    -183mA     -253.4mA   -113mA
-912mV    -135mA     -212.5mA   -83.33mA
-838mV    -63.16mA   -137.2mA   -62.66mA
-801mV    -43.93mA   -103.8mA   -56.25mA
-690mV    -21.49mA   -30.06mA   -34.72mA
-579mV    -9.043mA   -5.343mA   -15.31mA
-357mV    -110.3uA   -52.32uA   -166.6uA
1.8V      0A         0A         0A
[POWER_clamp]
|Voltage   I(typ)   I(min)   I(max)
-1.8V     22.96mA    14.12mA    42.58mA
-1.604V   19.99mA    12.25mA    37.59mA
-1.419V   16.97mA    10.35mA    32.49mA
-975mV    9.199mA    5.527mA    19.24mA
-864mV    7.174mA    4.324mA    15.6mA
-790mV    5.788mA    3.534mA    12.79mA
-679mV    3.605mA    2.374mA    7.249mA
-605mV    2.066mA    1.631mA    3.958mA
-531mV    820.6uA    942.6uA    1.61mA
-457mV    221.3uA    381uA      405.2uA
-272mV    4.708uA    6.259uA    4.369uA
1.8V      0A         0A         4.229nA
[Ramp]
| variable   typ   min   max
dV/dt_r   0.673/0.313n   0.481/0.454n   0.878/0.152n
dV/dt_f   0.667/0.295n   0.435/0.417n   0.865/0.178n
R_load = 50.000
[Rising Waveform]
R_fixture= 50.000
V_fixture= 0.0
V_fixture_min= 0.0
V_fixture_max= 0.0
|time   V(typ)   V(min)   V(max)
0s        3.652nV    38.62nV    2.158nV
699ps     44.57uV    26.96uV    -34.54mV
953ps     -288.4uV   2.052uV    1.259V
1.316ns   -26.64mV   116.8uV    1.425V
1.456ns   365mV      69.53uV    1.439V
1.758ns   922mV      -1.023mV   1.453V
2.331ns   1.076V     -12.85mV   1.462V
2.64ns    1.096V     419.5mV    1.463V
4.026ns   1.119V     773.2mV    1.464V
20ns      1.121V     801mV      1.464V
[Rising Waveform]
R_fixture= 50.000
V_fixture= 1.800
V_fixture_min= 1.710
V_fixture_max= 1.890
|time   V(typ)   V(min)   V(max)
0s        687.7mV    984.9mV    448.1mV
632ps     687.7mV    984.9mV    452.9mV
696ps     687.6mV    984.9mV    703.6mV
830ps     687.9mV    984.9mV    1.707V
1.154ns   713.7mV    984.8mV    1.869V
1.481ns   1.665V     986mV      1.882V
1.846ns   1.781V     958.2mV    1.887V
2.481ns   1.795V     1.612V     1.889V
2.828ns   1.797V     1.694V     1.89V
20ns      1.8V       1.71V      1.89V
[Falling Waveform]
R_fixture= 50.000
V_fixture= 1.800
V_fixture_min= 1.710
V_fixture_max= 1.890
|time   V(typ)   V(min)   V(max)
0s        1.8V       1.71V      1.89V
725ps     1.8V       1.71V      1.942V
980ps     1.801V     1.71V      720.9mV
1.372ns   1.851V     1.71V      480mV
1.49ns    1.528V     1.71V      468.9mV
1.823ns   866.9mV    1.711V     456.6mV
2.535ns   709.1mV    1.718V     449.1mV
2.953ns   697.1mV    1.194V     448.4mV
3.669ns   691.2mV    1.015V     448.1mV
20ns      687.6mV    984.8mV    448mV
[Falling Waveform]
R_fixture= 50.000
V_fixture= 0.0
V_fixture_min= 0.0
V_fixture_max= 0.0
|time   V(typ)   V(min)   V(max)
0s        1.121V     801mV      1.464V
683ps     1.121V     801.1mV    1.455V
871ps     1.121V     801.1mV    180.2mV
1.207ns   1.123V     801mV      18.28mV
1.566ns   129.7mV    801mV      6.295mV
1.929ns   16.51mV    799.8mV    1.964mV
2.261ns   8.085mV    752.8mV    747.4uV
2.743ns   3.04mV     79.5mV     203.7uV
3.315ns   957uV      8.573mV    70.21uV
20ns      -420.3nV   -224.1nV   -507.9nV
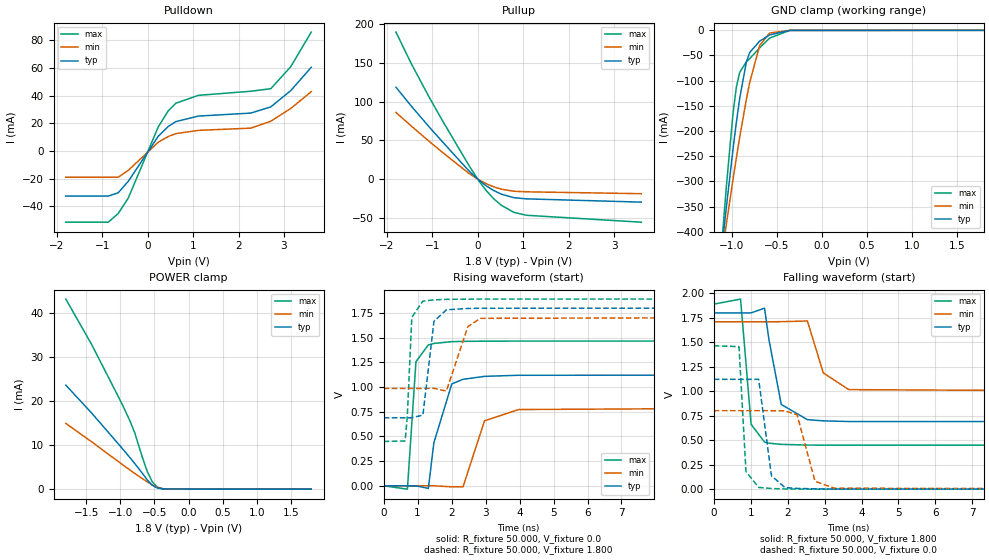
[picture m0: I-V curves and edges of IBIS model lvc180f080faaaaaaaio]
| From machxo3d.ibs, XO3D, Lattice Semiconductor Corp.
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|   Model lvc180f080faaaaaaaio
[Model] lvc180f080faaaaaaaio
Model_type I/O
Polarity   Non-Inverting
Enable   Active-Low
Vinl =  0.630V
Vinh =  1.170V
Vmeas =  0.900V
Cref =  0.0F
Rref =  1.000M
Vref =  0.0V
C_comp   4.200pF   3.800pF   7.500pF
[Temperature Range]   25.000   0.105k   -40.000
[Voltage Range]   1.800V   1.710V   1.890V
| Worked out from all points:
|   slope of the pulldown table from 0 to 0.27 V, typ, clamps not added: 22.7 ohm
|   slope of the pullup table from 0 to 0.27 V, typ, clamps not added: 22.8 ohm
|   GND clamp passes 1 mA (typ) near -0.44 V on its own axis
|   POWER clamp passes 1 mA (typ) near -0.54 V on its own axis
|   rising waveform, R_fixture 50.000, V_fixture 0.0: 20-80 % time 315ps typ, 457ps min, 151ps max; typ from 0.001 V to 1.12 V
|   rising waveform, R_fixture 50.000, V_fixture 1.800: 20-80 % time 207ps typ, 354ps min, 103ps max; typ from 0.689 V to 1.8 V
|   falling waveform, R_fixture 50.000, V_fixture 1.800: 20-80 % time 292ps typ, 398ps min, 177ps max; typ from 1.8 V to 0.689 V
|   falling waveform, R_fixture 50.000, V_fixture 0.0: 20-80 % time 178ps typ, 304ps min, 102ps max; typ from 1.12 V to 0.001 V
[Pulldown]
|Voltage   I(typ)   I(min)   I(max)
-1.8V     -32.67mA   -18.98mA   -51.52mA
-865mV    -32.67mA   -18.98mA   -51.52mA
-645mV    -30.22mA   -18.98mA   -45.17mA
-425mV    -21.97mA   -14.07mA   -34.06mA
235mV     10.62mA    6.321mA    17.45mA
455mV     17.66mA    10.44mA    28.95mA
620mV     21.15mA    12.46mA    34.42mA
1.115V    25.16mA    14.83mA    40.14mA
2.27V     27.33mA    16.45mA    43.11mA
2.71V     31.79mA    21.43mA    44.95mA
3.15V     43.59mA    30.69mA    60.86mA
3.6V      60.39mA    42.79mA    85.86mA
[Pullup]
|Voltage   I(typ)   I(min)   I(max)
-1.8V     118.7mA    86.06mA    189.8mA
-1.46V    94.14mA    68.51mA    148.9mA
-1.075V   67.84mA    49.1mA     106.5mA
-800mV    49.79mA    35.74mA    77.94mA
-195mV    10.76mA    7.525mA    17.82mA
25mV      -1.264mA   -864.3uA   -2.139mA
190mV     -8.744mA   -5.939mA   -14.93mA
355mV     -14.76mA   -9.939mA   -25.44mA
520mV     -19.33mA   -12.89mA   -33.74mA
795mV     -23.9mA    -15.59mA   -42.8mA
1.07V     -25.4mA    -16.32mA   -46.58mA
3.6V      -29.62mA   -18.74mA   -55.51mA
[GND_clamp]
|Voltage   I(typ)   I(min)   I(max)
-1.8V     -1.677A    -1.372A    -2.207A
-1.097V   -411.6mA   -430.5mA   -393mA
-1.06V    -351mA     -384.7mA   -309.9mA
-986mV    -235.9mA   -295.9mA   -164.7mA
-949mV    -183mA     -253.4mA   -113mA
-912mV    -135mA     -212.5mA   -83.35mA
-838mV    -63.17mA   -137.2mA   -62.69mA
-801mV    -43.94mA   -103.8mA   -56.28mA
-690mV    -21.51mA   -30.07mA   -34.75mA
-579mV    -9.065mA   -5.356mA   -15.35mA
-357mV    -147.5uA   -72.3uA    -237.1uA
1.8V      -12.41nA   0A         -10.91uA
[POWER_clamp]
|Voltage   I(typ)   I(min)   I(max)
-1.8V     23.65mA    14.95mA    43.22mA
-1.419V   17.27mA    10.75mA    32.84mA
-975mV    9.322mA    5.649mA    19.37mA
-864mV    7.265mA    4.408mA    15.69mA
-790mV    5.86mA     3.598mA    12.87mA
-679mV    3.655mA    2.417mA    7.32mA
-605mV    2.107mA    1.665mA    4.016mA
-531mV    854uA      968.7uA    1.658mA
-457mV    251.6uA    402uA      448.6uA
-383mV    77.17uA    103.3uA    115.3uA
-235mV    19.9uA     13.46uA    32.69uA
1.8V      0A         0A         0A
[Ramp]
| variable   typ   min   max
dV/dt_r   0.673/0.312n   0.481/0.454n   0.878/0.151n
dV/dt_f   0.667/0.296n   0.435/0.418n   0.864/0.179n
R_load = 50.000
[Rising Waveform]
R_fixture= 50.000
V_fixture= 0.0
V_fixture_min= 0.0
V_fixture_max= 0.0
|time   V(typ)   V(min)   V(max)
0s        542.4uV    393.2uV    769.5uV
699ps     587uV      419.8uV    -33.31mV
951ps     246.4uV    394.9uV    1.257V
1.316ns   -25.58mV   516.1uV    1.426V
1.477ns   435mV      460.5uV    1.441V
2.006ns   1.032V     -9.477mV   1.459V
2.337ns   1.078V     -8.378mV   1.462V
2.968ns   1.108V     657.7mV    1.464V
3.973ns   1.119V     772.3mV    1.465V
20ns      1.122V     801.9mV    1.465V
[Rising Waveform]
R_fixture= 50.000
V_fixture= 1.800
V_fixture_min= 1.710
V_fixture_max= 1.890
|time   V(typ)   V(min)   V(max)
0s        688.8mV    985.7mV    449.4mV
632ps     688.9mV    985.7mV    454.3mV
696ps     688.8mV    985.7mV    705.7mV
829ps     689.1mV    985.7mV    1.705V
1.155ns   716.5mV    985.6mV    1.869V
1.481ns   1.665V     986.9mV    1.882V
1.846ns   1.781V     959mV      1.887V
2.479ns   1.795V     1.611V     1.889V
2.845ns   1.797V     1.695V     1.89V
20ns      1.8V       1.71V      1.89V
[Falling Waveform]
R_fixture= 50.000
V_fixture= 1.800
V_fixture_min= 1.710
V_fixture_max= 1.890
|time   V(typ)   V(min)   V(max)
0s        1.8V       1.71V      1.89V
725ps     1.8V       1.71V      1.942V
1.011ns   1.801V     1.71V      662.6mV
1.374ns   1.849V     1.71V      481.2mV
1.493ns   1.528V     1.71V      470.1mV
1.827ns   865.7mV    1.711V     457.8mV
2.535ns   710.3mV    1.718V     450.9mV
2.964ns   698.1mV    1.188V     449.9mV
3.654ns   691.4mV    1.017V     449.5mV
20ns      688.9mV    985.6mV    449.3mV
[Falling Waveform]
R_fixture= 50.000
V_fixture= 0.0
V_fixture_min= 0.0
V_fixture_max= 0.0
|time   V(typ)   V(min)   V(max)
0s        1.122V     801.9mV    1.465V
683ps     1.122V     801.9mV    1.456V
872ps     1.122V     801.9mV    179.2mV
1.215ns   1.123V     801.9mV    18.53mV
1.561ns   137.4mV    801.9mV    7.058mV
1.927ns   17.19mV    800.7mV    2.713mV
2.256ns   8.33mV     759mV      1.506mV
2.741ns   3.791mV    81.16mV    967uV
3.265ns   1.607mV    9.95mV     836.6uV
20ns      542uV      393.1uV    768.9uV
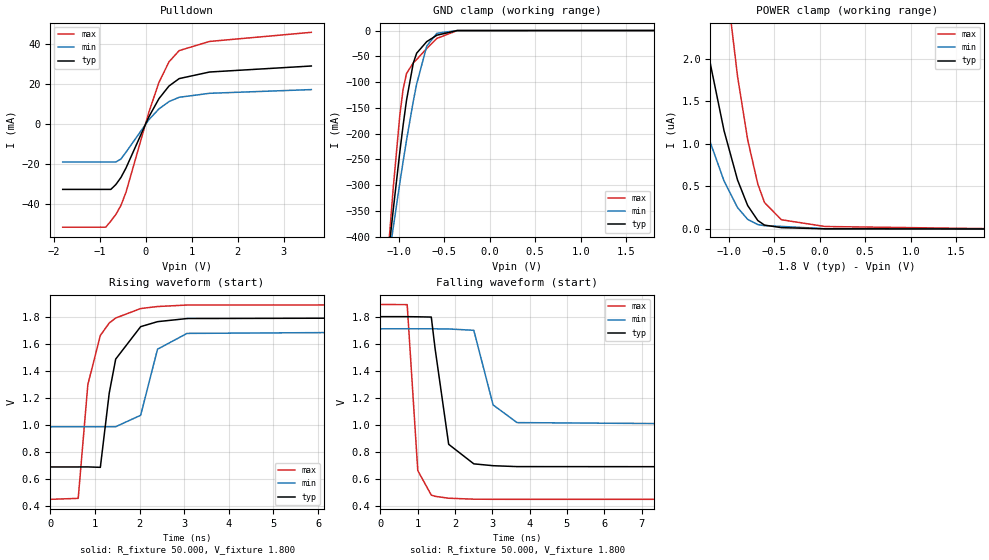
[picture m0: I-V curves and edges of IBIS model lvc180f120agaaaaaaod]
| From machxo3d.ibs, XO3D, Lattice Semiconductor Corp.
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|   Model lvc180f120agaaaaaaod
[Model] lvc180f120agaaaaaaod
Model_type I/O_open_drain
Polarity   Non-Inverting
Enable   Active-Low
Vinl =  0.630V
Vinh =  1.170V
Vmeas =  0.900V
Cref =  0.0F
Rref = 10.00k
Vref = 1.80V
C_comp   4.200pF   3.800pF   7.500pF
[Temperature Range]   25.000   0.105k   -40.000
[Voltage Range]   1.800V   1.710V   1.890V
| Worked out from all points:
|   slope of the pulldown table from 0 to 0.27 V, typ, clamps not added: 22.7 ohm
|   GND clamp passes 1 mA (typ) near -0.44 V on its own axis
|   rising waveform, R_fixture 50.000, V_fixture 1.800: 20-80 % time 344ps typ, 357ps min, 347ps max; typ from 0.688 V to 1.8 V
|   falling waveform, R_fixture 50.000, V_fixture 1.800: 20-80 % time 305ps typ, 431ps min, 184ps max; typ from 1.8 V to 0.688 V
[Pulldown]
|Voltage   I(typ)   I(min)   I(max)
-1.8V     -32.67mA   -18.98mA   -51.52mA
-865mV    -32.67mA   -18.98mA   -51.52mA
-755mV    -32.67mA   -18.98mA   -48.5mA
-645mV    -30.22mA   -18.98mA   -45.17mA
-535mV    -26.71mA   -17.49mA   -40.65mA
-425mV    -21.97mA   -14.07mA   -34.06mA
70mV      3.511mA    2.096mA    5.77mA
290mV     12.64mA    7.511mA    20.77mA
510mV     19mA       11.21mA    31.08mA
730mV     22.67mA    13.34mA    36.66mA
1.39V     25.96mA    15.33mA    41.23mA
3.6V      28.96mA    17.18mA    45.78mA
[GND_clamp]
|Voltage   I(typ)   I(min)   I(max)
-1.8V     -1.677A    -1.372A    -2.207A
-1.097V   -411.6mA   -430.5mA   -392.9mA
-1.06V    -351mA     -384.7mA   -309.8mA
-986mV    -235.9mA   -295.9mA   -164.7mA
-949mV    -183mA     -253.4mA   -113mA
-912mV    -135mA     -212.5mA   -83.33mA
-838mV    -63.16mA   -137.2mA   -62.66mA
-801mV    -43.93mA   -103.8mA   -56.25mA
-690mV    -21.49mA   -30.06mA   -34.72mA
-579mV    -9.043mA   -5.343mA   -15.31mA
-357mV    -110.3uA   -52.32uA   -166.6uA
1.8V      0A         0A         0A
[POWER_clamp]
|Voltage   I(typ)   I(min)   I(max)
-1.8V     6.918uA    4.075uA    15.53uA
-1.641V   5.335uA    3.081uA    12.17uA
-1.382V   3.16uA     1.741uA    7.507uA
-1.197V   1.931uA    1.01uA     4.843uA
-1.049V   1.156uA    564.3nA    3.128uA
-901mV    576.3nA    251.7nA    1.796uA
-790mV    276.2nA    113.2nA    1.051uA
-679mV    99.6nA     51.79nA    530.4nA
-605mV    45.39nA    37.91nA    310.9nA
-420mV    15.42nA    30.1nA     108.3nA
61mV      1.594nA    2.49nA     28.82nA
1.8V      0A         0A         4.229nA
[Ramp]
| variable   typ   min   max
dV/dt_r   0.667/0.343n   0.435/0.355n   0.865/0.347n
dV/dt_f   0.667/0.304n   0.435/0.429n   0.865/0.184n
R_load = 50.000
[Rising Waveform]
R_fixture= 50.000
V_fixture= 1.800
V_fixture_min= 1.710
V_fixture_max= 1.890
|time   V(typ)   V(min)   V(max)
0s        687.7mV    984.9mV    448.1mV
626ps     687.7mV    984.9mV    455.3mV
842ps     688mV      984.9mV    1.298V
1.122ns   684.9mV    984.8mV    1.661V
1.321ns   1.234V     984.9mV    1.753V
1.466ns   1.486V     985.7mV    1.79V
2.025ns   1.726V     1.07V      1.86V
2.403ns   1.763V     1.559V     1.875V
3.064ns   1.786V     1.676V     1.886V
20ns      1.8V       1.71V      1.89V
[Falling Waveform]
R_fixture= 50.000
V_fixture= 1.800
V_fixture_min= 1.710
V_fixture_max= 1.890
|time   V(typ)   V(min)   V(max)
0s        1.8V       1.71V      1.89V
721ps     1.8V       1.71V      1.889V
1.005ns   1.799V     1.71V      660.7mV
1.367ns   1.797V     1.71V      479.4mV
1.468ns   1.565V     1.71V      470.4mV
1.833ns   855.2mV    1.709V     456.2mV
2.506ns   710.7mV    1.699V     449.3mV
3.023ns   697mV      1.147V     448.3mV
3.664ns   690.3mV    1.016V     448.2mV
20ns      687.6mV    984.8mV    448.1mV
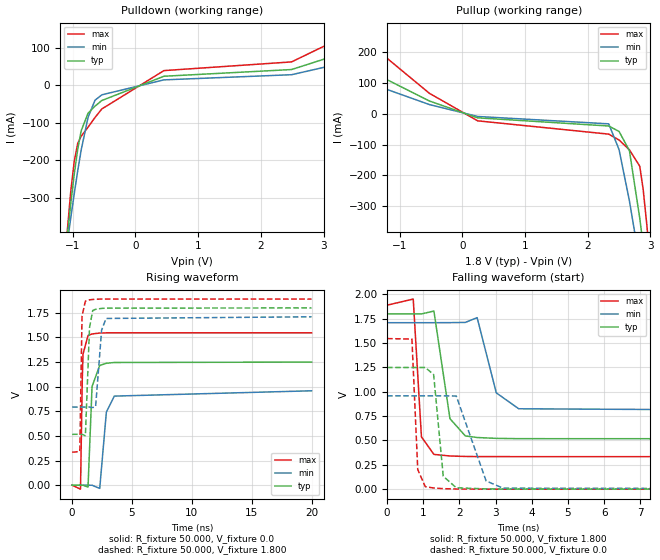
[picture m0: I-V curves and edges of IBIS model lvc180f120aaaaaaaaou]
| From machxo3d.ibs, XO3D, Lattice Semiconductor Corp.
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|   Model lvc180f120aaaaaaaaou
[Model] lvc180f120aaaaaaaaou
Model_type Output
Polarity   Non-Inverting
Enable   Active-High
Vmeas =  0.900V
Cref =  0.0F
Rref =  1.000M
Vref =  0.0V
C_comp   4.200pF   3.800pF   7.500pF
[Temperature Range]   25.000   0.105k   -40.000
[Voltage Range]   1.800V   1.710V   1.890V
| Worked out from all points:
|   slope of the pulldown table from 0 to 0.27 V, typ, clamps not added: 17 ohm
|   slope of the pullup table from 0 to 0.27 V, typ, clamps not added: 18.2 ohm
|   rising waveform, R_fixture 50.000, V_fixture 0.0: 20-80 % time 251ps typ, 432ps min, 121ps max; typ from 0 V to 1.25 V
|   rising waveform, R_fixture 50.000, V_fixture 1.800: 20-80 % time 192ps typ, 340ps min, 90.8ps max; typ from 0.517 V to 1.8 V
|   falling waveform, R_fixture 50.000, V_fixture 1.800: 20-80 % time 238ps typ, 390ps min, 132ps max; typ from 1.8 V to 0.517 V
|   falling waveform, R_fixture 50.000, V_fixture 0.0: 20-80 % time 163ps typ, 292ps min, 87ps max; typ from 1.25 V to 0 V
[Pulldown]
|Voltage   I(typ)   I(min)   I(max)
-1.8V     -1.679A    -1.373A    -2.209A
-1.085V   -400.2mA   -419.6mA   -385.9mA
-1.03V    -314.7mA   -352.9mA   -282.1mA
-975mV    -236.9mA   -288.9mA   -202.8mA
-920mV    -171.4mA   -228.5mA   -155.4mA
-865mV    -121.7mA   -173.2mA   -136.4mA
-755mV    -75.06mA   -86.02mA   -112.2mA
-645mV    -56.23mA   -40.43mA   -86.51mA
-535mV    -41.04mA   -25.93mA   -63.51mA
455mV     23.55mA    13.92mA    38.6mA
2.49V     41.41mA    27.64mA    61.76mA
3.6V      100.9mA    69.84mA    151.5mA
[Pullup]
|Voltage   I(typ)   I(min)   I(max)
-1.8V     171.3mA    121.7mA    280mA
-525mV    40.89mA    29.34mA    65.83mA
245mV     -13.64mA   -9.238mA   -23.35mA
2.335V    -40.04mA   -33.09mA   -66.38mA
2.5V      -57.82mA   -116.8mA   -85.42mA
2.665V    -120mA     -282.7mA   -117.3mA
2.83V     -339mA     -482.1mA   -170.3mA
2.885V    -427.7mA   -552.2mA   -246.8mA
2.94V     -519.9mA   -623.4mA   -355.2mA
2.995V    -614.3mA   -695.6mA   -478.7mA
3.05V     -710.5mA   -768.5mA   -609.8mA
3.6V      -1.714A    -1.52A     -2.036A
[Ramp]
| variable   typ   min   max
dV/dt_r   0.750/0.252n   0.575/0.427n   0.928/0.120n
dV/dt_f   0.770/0.237n   0.550/0.391n   0.933/0.132n
R_load = 50.000
[Rising Waveform]
R_fixture= 50.000
V_fixture= 0.0
V_fixture_min= 0.0
V_fixture_max= 0.0
|time   V(typ)   V(min)   V(max)
0s        2.942nV    32.1nV     1.699nV
700ps     42.3uV     24.12uV    -40.27mV
843ps     40.89uV    24.12uV    1.049V
907ps     -117.7uV   -832.9nV   1.33V
1.328ns   -19.19mV   117.2uV    1.52V
1.665ns   1.002V     -442.2uV   1.536V
2.305ns   1.216V     -32.69mV   1.545V
2.859ns   1.238V     742mV      1.547V
3.521ns   1.246V     904.6mV    1.547V
20ns      1.25V      958.6mV    1.547V
[Rising Waveform]
R_fixture= 50.000
V_fixture= 1.800
V_fixture_min= 1.710
V_fixture_max= 1.890
|time   V(typ)   V(min)   V(max)
0s        516.8mV    793.5mV    334.2mV
643ps     516.8mV    793.5mV    343.1mV
827ps     516.9mV    793.5mV    1.716V
1.108ns   501.7mV    793.4mV    1.869V
1.453ns   1.601V     793.9mV    1.882V
1.72ns    1.774V     788.6mV    1.886V
1.962ns   1.786V     798mV      1.888V
2.463ns   1.795V     1.575V     1.89V
2.835ns   1.798V     1.693V     1.89V
20ns      1.8V       1.71V      1.89V
[Falling Waveform]
R_fixture= 50.000
V_fixture= 1.800
V_fixture_min= 1.710
V_fixture_max= 1.890
|time   V(typ)   V(min)   V(max)
0s        1.8V       1.71V      1.89V
724ps     1.8V       1.71V      1.953V
951ps     1.8V       1.71V      537.4mV
1.295ns   1.83V      1.71V      357.2mV
1.739ns   724mV      1.711V     340.9mV
2.164ns   547mV      1.713V     336mV
2.49ns    530.7mV    1.762V     334.9mV
3.019ns   521.8mV    989.6mV    334.4mV
3.639ns   518.7mV    825.9mV    334.2mV
20ns      516.8mV    793.5mV    334.2mV
[Falling Waveform]
R_fixture= 50.000
V_fixture= 0.0
V_fixture_min= 0.0
V_fixture_max= 0.0
|time   V(typ)   V(min)   V(max)
0s        1.25V      958.6mV    1.547V
688ps     1.25V      958.6mV    1.542V
849ps     1.25V      958.6mV    201.4mV
1.058ns   1.25V      958.6mV    24.92mV
1.288ns   1.177V     958.6mV    12.44mV
1.553ns   132.6mV    958.6mV    5.208mV
1.913ns   14.52mV    957.2mV    1.661mV
2.738ns   2.735mV    84.29mV    196uV
3.206ns   986.9uV    10.33mV    60.09uV
20ns      -219.1nV   -3.755nV   -88.11nV
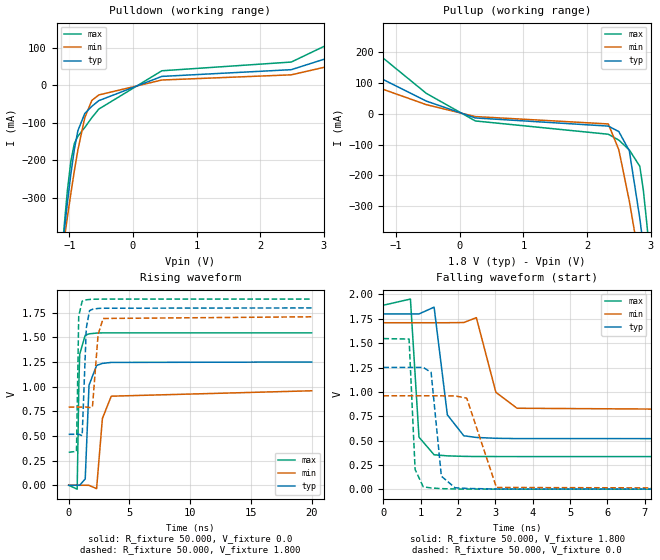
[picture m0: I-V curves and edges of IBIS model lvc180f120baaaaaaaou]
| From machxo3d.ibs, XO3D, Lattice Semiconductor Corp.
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|   Model lvc180f120baaaaaaaou
[Model] lvc180f120baaaaaaaou
Model_type Output
Polarity   Non-Inverting
Enable   Active-High
Vmeas =  0.900V
Cref =  0.0F
Rref =  1.000M
Vref =  0.0V
C_comp   4.200pF   3.800pF   7.500pF
[Temperature Range]   25.000   0.105k   -40.000
[Voltage Range]   1.800V   1.710V   1.890V
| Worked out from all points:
|   slope of the pulldown table from 0 to 0.27 V, typ, clamps not added: 17 ohm
|   slope of the pullup table from 0 to 0.27 V, typ, clamps not added: 18.2 ohm
|   rising waveform, R_fixture 50.000, V_fixture 0.0: 20-80 % time 252ps typ, 431ps min, 121ps max; typ from 0 V to 1.25 V
|   rising waveform, R_fixture 50.000, V_fixture 1.800: 20-80 % time 192ps typ, 339ps min, 90.7ps max; typ from 0.518 V to 1.8 V
|   falling waveform, R_fixture 50.000, V_fixture 1.800: 20-80 % time 236ps typ, 391ps min, 133ps max; typ from 1.8 V to 0.518 V
|   falling waveform, R_fixture 50.000, V_fixture 0.0: 20-80 % time 163ps typ, 291ps min, 87.1ps max; typ from 1.25 V to 0 V
[Pulldown]
|Voltage   I(typ)   I(min)   I(max)
-1.8V     -1.679A    -1.373A    -2.209A
-1.085V   -400.2mA   -419.6mA   -385.9mA
-1.03V    -314.7mA   -352.9mA   -282.1mA
-975mV    -236.9mA   -288.9mA   -202.9mA
-920mV    -171.4mA   -228.5mA   -155.4mA
-865mV    -121.7mA   -173.2mA   -136.4mA
-755mV    -75.08mA   -86.02mA   -112.3mA
-645mV    -56.25mA   -40.44mA   -86.54mA
-535mV    -41.07mA   -25.94mA   -63.56mA
455mV     23.51mA    13.9mA     38.51mA
2.49V     41.46mA    27.7mA     61.81mA
3.6V      101.5mA    70.82mA    152mA
[Pullup]
|Voltage   I(typ)   I(min)   I(max)
-1.8V     172.1mA    122.6mA    280.6mA
-525mV    40.92mA    29.37mA    65.88mA
245mV     -13.65mA   -9.247mA   -23.38mA
2.335V    -40.06mA   -33.09mA   -66.43mA
2.5V      -57.83mA   -116.8mA   -85.45mA
2.665V    -120mA     -282.7mA   -117.3mA
2.83V     -339mA     -482.1mA   -170.3mA
2.885V    -427.7mA   -552.2mA   -246.8mA
2.94V     -519.9mA   -623.4mA   -355.3mA
2.995V    -614.3mA   -695.6mA   -478.7mA
3.05V     -710.5mA   -768.5mA   -609.8mA
3.6V      -1.714A    -1.52A     -2.036A
[Ramp]
| variable   typ   min   max
dV/dt_r   0.750/0.252n   0.575/0.427n   0.928/0.120n
dV/dt_f   0.769/0.237n   0.549/0.392n   0.933/0.133n
R_load = 50.000
[Rising Waveform]
R_fixture= 50.000
V_fixture= 0.0
V_fixture_min= 0.0
V_fixture_max= 0.0
|time   V(typ)   V(min)   V(max)
0s        437uV      326.8uV    605.6uV
700ps     478.7uV    350.6uV    -39.23mV
842ps     486.1uV    350.6uV    1.044V
907ps     321.9uV    350.6uV    1.331V
1.363ns   65.19mV    476.1uV    1.523V
1.675ns   1.016V     -93.69uV   1.537V
2.299ns   1.216V     -34.2mV    1.545V
2.777ns   1.237V     678.6mV    1.547V
3.508ns   1.247V     904.4mV    1.547V
20ns      1.251V     959.2mV    1.547V
[Rising Waveform]
R_fixture= 50.000
V_fixture= 1.800
V_fixture_min= 1.710
V_fixture_max= 1.890
|time   V(typ)   V(min)   V(max)
0s        517.6mV    794.2mV    335.1mV
643ps     517.6mV    794.2mV    344.1mV
827ps     518mV      794.2mV    1.717V
1.112ns   503.4mV    794.2mV    1.869V
1.451ns   1.596V     794.7mV    1.882V
1.72ns    1.773V     789.3mV    1.886V
1.958ns   1.786V     795.5mV    1.888V
2.422ns   1.795V     1.531V     1.889V
2.838ns   1.797V     1.693V     1.89V
20ns      1.8V       1.71V      1.89V
[Falling Waveform]
R_fixture= 50.000
V_fixture= 1.800
V_fixture_min= 1.710
V_fixture_max= 1.890
|time   V(typ)   V(min)   V(max)
0s        1.8V       1.71V      1.89V
724ps     1.8V       1.71V      1.953V
953ps     1.8V       1.71V      534.5mV
1.358ns   1.87V      1.71V      353.6mV
1.713ns   763.8mV    1.71V      342.3mV
2.153ns   548.7mV    1.712V     337.4mV
2.49ns    531.5mV    1.762V     335.7mV
3.013ns   522.9mV    995.3mV    335.3mV
3.579ns   519.9mV    831.4mV    335.2mV
20ns      517.5mV    794.2mV    335.1mV
[Falling Waveform]
R_fixture= 50.000
V_fixture= 0.0
V_fixture_min= 0.0
V_fixture_max= 0.0
|time   V(typ)   V(min)   V(max)
0s        1.251V     959.2mV    1.547V
688ps     1.251V     959.3mV    1.542V
849ps     1.251V     959.3mV    202.9mV
1.066ns   1.251V     959.3mV    24.74mV
1.278ns   1.2V       959.3mV    12.83mV
1.553ns   133.7mV    959.2mV    5.774mV
1.918ns   14.78mV    957.9mV    2.237mV
2.232ns   7.747mV    935.5mV    1.323mV
3.028ns   1.894mV    17.71mV    719.7uV
20ns      436.9uV    326.8uV    605.4uV
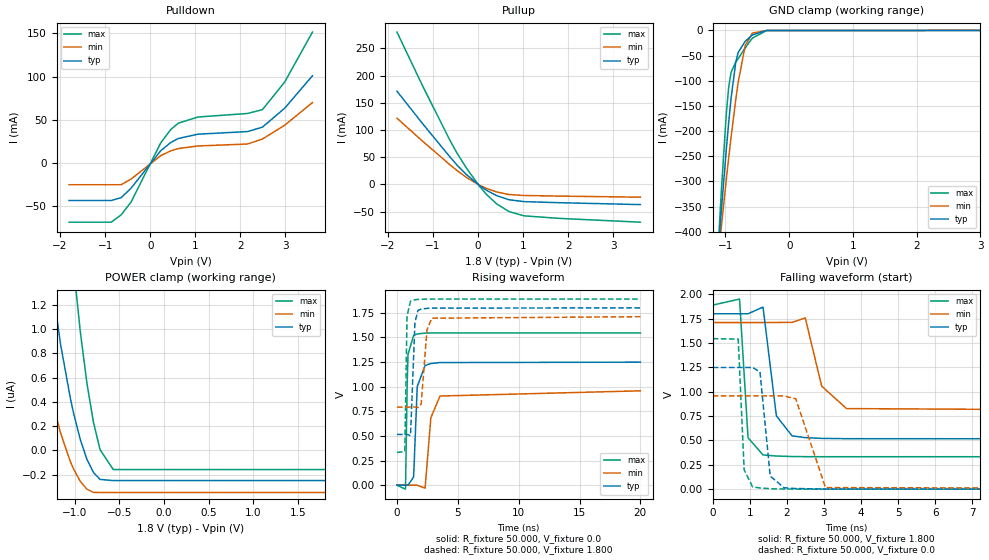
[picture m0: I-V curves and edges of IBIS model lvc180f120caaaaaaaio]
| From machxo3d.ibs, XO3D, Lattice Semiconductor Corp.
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|   Model lvc180f120caaaaaaaio
[Model] lvc180f120caaaaaaaio
Model_type I/O
Polarity   Non-Inverting
Enable   Active-Low
Vinl =  0.630V
Vinh =  1.170V
Vmeas =  0.900V
Cref =  0.0F
Rref =  1.000M
Vref =  0.0V
C_comp   4.200pF   3.800pF   7.500pF
[Temperature Range]   25.000   0.105k   -40.000
[Voltage Range]   1.800V   1.710V   1.890V
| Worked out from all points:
|   slope of the pulldown table from 0 to 0.27 V, typ, clamps not added: 17 ohm
|   slope of the pullup table from 0 to 0.27 V, typ, clamps not added: 18.2 ohm
|   GND clamp passes 1 mA (typ) near -0.44 V on its own axis
|   rising waveform, R_fixture 50.000, V_fixture 0.0: 20-80 % time 252ps typ, 433ps min, 121ps max; typ from 0 V to 1.25 V
|   rising waveform, R_fixture 50.000, V_fixture 1.800: 20-80 % time 192ps typ, 340ps min, 90.9ps max; typ from 0.515 V to 1.8 V
|   falling waveform, R_fixture 50.000, V_fixture 1.800: 20-80 % time 235ps typ, 387ps min, 132ps max; typ from 1.8 V to 0.515 V
|   falling waveform, R_fixture 50.000, V_fixture 0.0: 20-80 % time 162ps typ, 292ps min, 86.7ps max; typ from 1.25 V to 0 V
[Pulldown]
|Voltage   I(typ)   I(min)   I(max)
-1.8V     -43.56mA   -25.31mA   -68.69mA
-865mV    -43.56mA   -25.31mA   -68.69mA
-645mV    -40.3mA    -25.31mA   -60.23mA
-425mV    -29.3mA    -18.76mA   -45.41mA
235mV     14.17mA    8.428mA    23.27mA
455mV     23.55mA    13.92mA    38.6mA
620mV     28.2mA     16.61mA    45.89mA
1.06V     33.26mA    19.6mA     53.12mA
2.16V     36.29mA    21.86mA    57.24mA
2.49V     41.38mA    27.64mA    61.66mA
2.985V    63.44mA    43.72mA    93.79mA
3.6V      100.9mA    69.87mA    151.5mA
[Pullup]
|Voltage   I(typ)   I(min)   I(max)
-1.8V     171.4mA    121.7mA    280mA
-1.24V    112.6mA    80.11mA    182.6mA
-635mV    51.67mA    36.83mA    82.71mA
-470mV    35.8mA     25.67mA    57.83mA
-250mV    17.59mA    12.36mA    28.98mA
25mV      -1.58mA    -1.08mA    -2.674mA
190mV     -10.93mA   -7.424mA   -18.66mA
410mV     -20.55mA   -13.8mA    -35.57mA
685mV     -28.15mA   -18.54mA   -49.84mA
1.015V    -31.54mA   -20.29mA   -57.67mA
1.785V    -33.53mA   -21.4mA    -62.31mA
3.6V      -37.02mA   -23.42mA   -69.38mA
[GND_clamp]
|Voltage   I(typ)   I(min)   I(max)
-1.8V     -1.677A    -1.372A    -2.207A
-1.097V   -411.7mA   -430.5mA   -393mA
-1.06V    -351mA     -384.7mA   -309.9mA
-986mV    -235.9mA   -295.9mA   -164.8mA
-949mV    -183mA     -253.4mA   -113.1mA
-912mV    -135mA     -212.5mA   -83.39mA
-838mV    -63.2mA    -137.2mA   -62.73mA
-801mV    -43.97mA   -103.8mA   -56.32mA
-690mV    -21.54mA   -30.09mA   -34.79mA
-579mV    -9.102mA   -5.388mA   -15.4mA
-357mV    -191.3uA   -96.81uA   -298.1uA
3.6V      109.7uA    43.11uA    257.2uA
[POWER_clamp]
|Voltage   I(typ)   I(min)   I(max)
-1.8V     5.719uA    2.929uA    14.07uA
-1.567V   3.495uA    1.63uA     8.906uA
-1.308V   1.654uA    574.5nA    4.658uA
-1.16V    879.1nA    145.5nA    2.867uA
-1.049V   428.7nA    -92.09nA   1.807uA
-1.012V   303.4nA    -154.9nA   1.506uA
-938mV    90.16nA    -254.7nA   980.2nA
-864mV    -72.34nA   -318.6nA   555.1nA
-790mV    -182.4nA   -345.7nA   230.4nA
-716mV    -238.9nA   -346.3nA   6.03nA
-568mV    -248.1nA   -346.3nA   -157.2nA
1.8V      -248.1nA   -346.3nA   -157.2nA
[Ramp]
| variable   typ   min   max
dV/dt_r   0.749/0.253n   0.574/0.427n   0.927/0.120n
dV/dt_f   0.770/0.236n   0.550/0.390n   0.933/0.132n
R_load = 50.000
[Rising Waveform]
R_fixture= 50.000
V_fixture= 0.0
V_fixture_min= 0.0
V_fixture_max= 0.0
|time   V(typ)   V(min)   V(max)
0s        2.84nV     31.79nV    1.575nV
700ps     42.3uV     24.07uV    -40.15mV
842ps     39.46uV    24.07uV    1.041V
907ps     -125.1uV   -865.4nV   1.328V
1.369ns   83.75mV    151.8uV    1.52V
1.665ns   999.9mV    -442uV     1.534V
2.311ns   1.214V     -30.03mV   1.543V
2.786ns   1.234V     685.1mV    1.544V
3.535ns   1.244V     904.5mV    1.544V
20ns      1.248V     957.3mV    1.544V
[Rising Waveform]
R_fixture= 50.000
V_fixture= 1.800
V_fixture_min= 1.710
V_fixture_max= 1.890
|time   V(typ)   V(min)   V(max)
0s        515.2mV    792.2mV    332.7mV
643ps     515.2mV    792.2mV    341.4mV
828ps     515.3mV    792.2mV    1.717V
1.114ns   501.7mV    792.1mV    1.867V
1.478ns   1.65V      793.3mV    1.881V
1.72ns    1.772V     787.3mV    1.884V
1.989ns   1.786V     823.5mV    1.886V
2.463ns   1.794V     1.573V     1.888V
2.857ns   1.796V     1.694V     1.888V
20ns      1.799V     1.709V     1.888V
[Falling Waveform]
R_fixture= 50.000
V_fixture= 1.800
V_fixture_min= 1.710
V_fixture_max= 1.890
|time   V(typ)   V(min)   V(max)
0s        1.799V     1.709V     1.888V
724ps     1.799V     1.709V     1.95V
953ps     1.799V     1.709V     527.5mV
1.357ns   1.868V     1.709V     351mV
1.717ns   752.5mV    1.71V      339.8mV
2.139ns   547.1mV    1.711V     334.8mV
2.497ns   528.8mV    1.756V     333.4mV
2.938ns   520.8mV    1.057V     332.9mV
3.61ns    517.7mV    826.6mV    332.8mV
20ns      515.2mV    792.2mV    332.7mV
[Falling Waveform]
R_fixture= 50.000
V_fixture= 0.0
V_fixture_min= 0.0
V_fixture_max= 0.0
|time   V(typ)   V(min)   V(max)
0s        1.248V     957.3mV    1.544V
688ps     1.248V     957.4mV    1.539V
849ps     1.248V     957.4mV    197.9mV
1.077ns   1.248V     957.3mV    22.4mV
1.275ns   1.203V     957.3mV    12.52mV
1.551ns   134.1mV    957.3mV    4.793mV
1.927ns   13.84mV    955.8mV    1.435mV
2.24ns    6.669mV    926.8mV    592.3uV
3.041ns   1.535mV    16.39mV    73.18uV
20ns      -112.2nV   71.82nV    -460.1nV
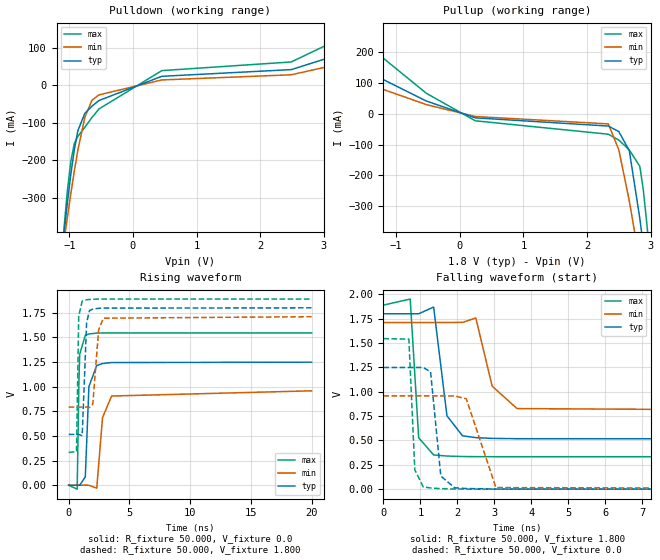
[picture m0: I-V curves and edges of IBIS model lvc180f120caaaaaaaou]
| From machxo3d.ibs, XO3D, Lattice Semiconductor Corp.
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|   Model lvc180f120caaaaaaaou
[Model] lvc180f120caaaaaaaou
Model_type Output
Polarity   Non-Inverting
Enable   Active-High
Vmeas =  0.900V
Cref =  0.0F
Rref =  1.000M
Vref =  0.0V
C_comp   4.200pF   3.800pF   7.500pF
[Temperature Range]   25.000   0.105k   -40.000
[Voltage Range]   1.800V   1.710V   1.890V
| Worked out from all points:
|   slope of the pulldown table from 0 to 0.27 V, typ, clamps not added: 16.9 ohm
|   slope of the pullup table from 0 to 0.27 V, typ, clamps not added: 18.2 ohm
|   rising waveform, R_fixture 50.000, V_fixture 0.0: 20-80 % time 252ps typ, 433ps min, 121ps max; typ from 0 V to 1.25 V
|   rising waveform, R_fixture 50.000, V_fixture 1.800: 20-80 % time 192ps typ, 340ps min, 90.9ps max; typ from 0.515 V to 1.8 V
|   falling waveform, R_fixture 50.000, V_fixture 1.800: 20-80 % time 235ps typ, 387ps min, 132ps max; typ from 1.8 V to 0.515 V
|   falling waveform, R_fixture 50.000, V_fixture 0.0: 20-80 % time 162ps typ, 292ps min, 86.7ps max; typ from 1.25 V to 0 V
[Pulldown]
|Voltage   I(typ)   I(min)   I(max)
-1.8V     -1.679A    -1.373A    -2.209A
-1.085V   -400.2mA   -419.6mA   -385.9mA
-1.03V    -314.7mA   -352.9mA   -282.2mA
-975mV    -236.9mA   -288.9mA   -202.9mA
-920mV    -171.5mA   -228.5mA   -155.5mA
-865mV    -121.8mA   -173.2mA   -136.5mA
-755mV    -75.11mA   -86.04mA   -112.3mA
-645mV    -56.28mA   -40.47mA   -86.59mA
-535mV    -41.11mA   -25.98mA   -63.61mA
455mV     23.63mA    13.95mA    38.77mA
2.49V     41.48mA    27.68mA    61.9mA
3.6V      101mA      69.92mA    151.8mA
[Pullup]
|Voltage   I(typ)   I(min)   I(max)
-1.8V     171.5mA    121.8mA    280.3mA
-525mV    40.97mA    29.37mA    66mA
245mV     -13.54mA   -9.201mA   -23.11mA
2.335V    -40.1mA    -33.12mA   -66.49mA
2.5V      -57.85mA   -116.8mA   -85.48mA
2.665V    -120mA     -282.7mA   -117.4mA
2.83V     -339mA     -482.1mA   -170.3mA
2.885V    -427.7mA   -552.2mA   -246.8mA
2.94V     -519.9mA   -623.4mA   -355.3mA
2.995V    -614.4mA   -695.6mA   -478.7mA
3.05V     -710.5mA   -768.5mA   -609.8mA
3.6V      -1.714A    -1.52A     -2.036A
[Ramp]
| variable   typ   min   max
dV/dt_r   0.749/0.253n   0.574/0.427n   0.927/0.120n
dV/dt_f   0.770/0.236n   0.550/0.390n   0.933/0.132n
R_load = 50.000
[Rising Waveform]
R_fixture= 50.000
V_fixture= 0.0
V_fixture_min= 0.0
V_fixture_max= 0.0
|time   V(typ)   V(min)   V(max)
0s        2.84nV     31.79nV    1.575nV
700ps     42.3uV     24.07uV    -40.15mV
842ps     39.46uV    24.07uV    1.041V
907ps     -125.1uV   -865.4nV   1.328V
1.369ns   83.75mV    151.8uV    1.52V
1.665ns   999.9mV    -442uV     1.534V
2.311ns   1.214V     -30.03mV   1.543V
2.786ns   1.234V     685.1mV    1.544V
3.535ns   1.244V     904.5mV    1.544V
20ns      1.248V     957.3mV    1.544V
[Rising Waveform]
R_fixture= 50.000
V_fixture= 1.800
V_fixture_min= 1.710
V_fixture_max= 1.890
|time   V(typ)   V(min)   V(max)
0s        515.2mV    792.2mV    332.7mV
643ps     515.2mV    792.2mV    341.4mV
828ps     515.3mV    792.2mV    1.717V
1.114ns   501.7mV    792.1mV    1.867V
1.478ns   1.65V      793.3mV    1.881V
1.72ns    1.772V     787.3mV    1.884V
1.989ns   1.786V     823.5mV    1.886V
2.463ns   1.794V     1.573V     1.888V
2.857ns   1.796V     1.694V     1.888V
20ns      1.799V     1.709V     1.888V
[Falling Waveform]
R_fixture= 50.000
V_fixture= 1.800
V_fixture_min= 1.710
V_fixture_max= 1.890
|time   V(typ)   V(min)   V(max)
0s        1.799V     1.709V     1.888V
724ps     1.799V     1.709V     1.95V
953ps     1.799V     1.709V     527.5mV
1.357ns   1.868V     1.709V     351mV
1.717ns   752.5mV    1.71V      339.8mV
2.139ns   547.1mV    1.711V     334.8mV
2.497ns   528.8mV    1.756V     333.4mV
2.938ns   520.8mV    1.057V     332.9mV
3.61ns    517.7mV    826.6mV    332.8mV
20ns      515.2mV    792.2mV    332.7mV
[Falling Waveform]
R_fixture= 50.000
V_fixture= 0.0
V_fixture_min= 0.0
V_fixture_max= 0.0
|time   V(typ)   V(min)   V(max)
0s        1.248V     957.3mV    1.544V
688ps     1.248V     957.4mV    1.539V
849ps     1.248V     957.4mV    197.9mV
1.077ns   1.248V     957.3mV    22.4mV
1.275ns   1.203V     957.3mV    12.52mV
1.551ns   134.1mV    957.3mV    4.793mV
1.927ns   13.84mV    955.8mV    1.435mV
2.24ns    6.669mV    926.8mV    592.3uV
3.041ns   1.535mV    16.39mV    73.18uV
20ns      -112.2nV   71.82nV    -460.1nV
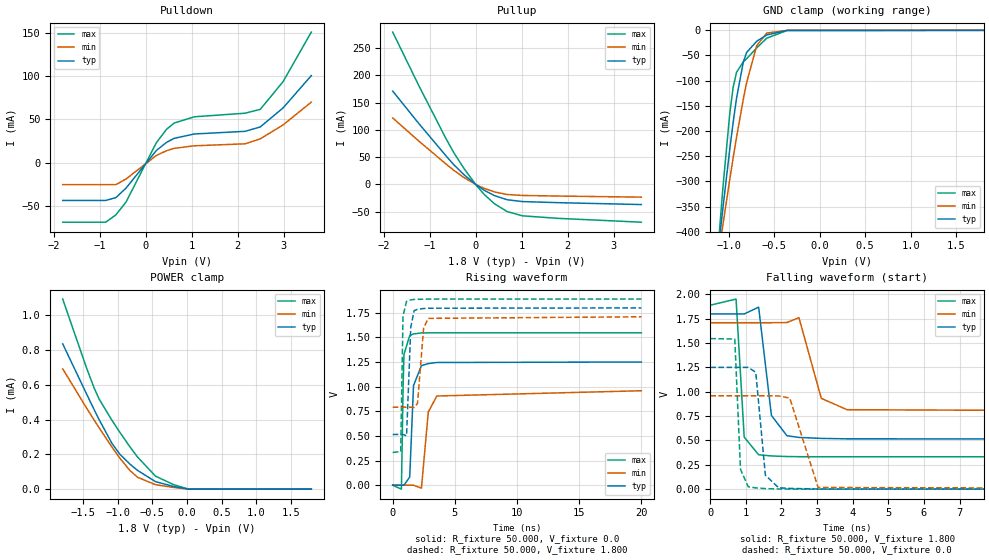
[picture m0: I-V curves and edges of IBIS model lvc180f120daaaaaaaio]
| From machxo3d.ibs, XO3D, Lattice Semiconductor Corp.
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|   Model lvc180f120daaaaaaaio
[Model] lvc180f120daaaaaaaio
Model_type I/O
Polarity   Non-Inverting
Enable   Active-Low
Vinl =  0.630V
Vinh =  1.170V
Vmeas =  0.900V
Cref =  0.0F
Rref =  1.000M
Vref =  0.0V
C_comp   4.200pF   3.800pF   7.500pF
[Temperature Range]   25.000   0.105k   -40.000
[Voltage Range]   1.800V   1.710V   1.890V
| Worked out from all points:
|   slope of the pulldown table from 0 to 0.27 V, typ, clamps not added: 17 ohm
|   slope of the pullup table from 0 to 0.27 V, typ, clamps not added: 18.2 ohm
|   GND clamp passes 1 mA (typ) near -0.44 V on its own axis
|   rising waveform, R_fixture 50.000, V_fixture 0.0: 20-80 % time 255ps typ, 436ps min, 122ps max; typ from 0 V to 1.25 V
|   rising waveform, R_fixture 50.000, V_fixture 1.800: 20-80 % time 193ps typ, 340ps min, 91.1ps max; typ from 0.515 V to 1.8 V
|   falling waveform, R_fixture 50.000, V_fixture 1.800: 20-80 % time 238ps typ, 394ps min, 133ps max; typ from 1.8 V to 0.515 V
|   falling waveform, R_fixture 50.000, V_fixture 0.0: 20-80 % time 163ps typ, 291ps min, 87.2ps max; typ from 1.25 V to 0 V
[Pulldown]
|Voltage   I(typ)   I(min)   I(max)
-1.8V     -43.56mA   -25.31mA   -68.69mA
-865mV    -43.56mA   -25.31mA   -68.69mA
-645mV    -40.3mA    -25.31mA   -60.23mA
-425mV    -29.3mA    -18.76mA   -45.41mA
235mV     14.17mA    8.428mA    23.27mA
455mV     23.55mA    13.92mA    38.6mA
620mV     28.2mA     16.61mA    45.89mA
1.06V     33.26mA    19.6mA     53.12mA
2.16V     36.3mA     21.87mA    57.24mA
2.49V     41.36mA    27.61mA    61.68mA
2.985V    63.29mA    43.65mA    93.61mA
3.6V      100.7mA    70.07mA    151mA
[Pullup]
|Voltage   I(typ)   I(min)   I(max)
-1.8V     171.2mA    121.9mA    279.5mA
-1.24V    112.4mA    80.04mA    182.4mA
-635mV    51.65mA    36.82mA    82.7mA
-470mV    35.81mA    25.67mA    57.86mA
-250mV    17.59mA    12.36mA    28.98mA
25mV      -1.58mA    -1.08mA    -2.674mA
190mV     -10.93mA   -7.424mA   -18.66mA
410mV     -20.55mA   -13.8mA    -35.57mA
685mV     -28.15mA   -18.54mA   -49.84mA
1.015V    -31.54mA   -20.29mA   -57.67mA
1.785V    -33.53mA   -21.4mA    -62.31mA
3.6V      -37.02mA   -23.42mA   -69.38mA
[GND_clamp]
|Voltage   I(typ)   I(min)   I(max)
-1.8V     -1.677A    -1.372A    -2.207A
-1.097V   -411.7mA   -430.5mA   -393mA
-1.06V    -351mA     -384.7mA   -309.9mA
-986mV    -235.9mA   -295.9mA   -164.8mA
-949mV    -183mA     -253.4mA   -113.1mA
-912mV    -135mA     -212.5mA   -83.39mA
-838mV    -63.2mA    -137.2mA   -62.73mA
-801mV    -43.97mA   -103.8mA   -56.32mA
-690mV    -21.54mA   -30.09mA   -34.79mA
-579mV    -9.102mA   -5.388mA   -15.4mA
-357mV    -191.3uA   -96.81uA   -298.1uA
1.8V      -12.41nA   0A         -10.91uA
[POWER_clamp]
|Voltage   I(typ)   I(min)   I(max)
-1.8V     836.1uA    692.5uA    1.094mA
-1.456V   549uA      467.8uA    698.7uA
-1.345V   458uA      397.8uA    582.4uA
-1.271V   398.7uA    352uA      517.3uA
-1.086V   262.9uA    241.7uA    395.6uA
-975mV    202uA      179.8uA    328.7uA
-827mV    144.5uA    107.4uA    243.8uA
-716mV    108uA      68.49uA    184.9uA
-457mV    43.42uA    25.76uA    75.17uA
-198mV    15.77uA    10.09uA    26.67uA
24mV      0A         0A         0A
1.8V      0A         0A         0A
[Ramp]
| variable   typ   min   max
dV/dt_r   0.751/0.254n   0.576/0.430n   0.928/0.121n
dV/dt_f   0.771/0.239n   0.551/0.394n   0.934/0.133n
R_load = 50.000
[Rising Waveform]
R_fixture= 50.000
V_fixture= 0.0
V_fixture_min= 0.0
V_fixture_max= 0.0
|time   V(typ)   V(min)   V(max)
0s        2.84nV     31.79nV    1.575nV
700ps     42.3uV     24.05uV    -40.15mV
842ps     39.46uV    24.05uV    1.041V
907ps     -125.1uV   -868.2nV   1.328V
1.369ns   83.75mV    151.8uV    1.52V
1.673ns   1.011V     -442uV     1.536V
2.311ns   1.214V     -30.03mV   1.546V
2.862ns   1.235V     743mV      1.547V
3.552ns   1.246V     905.8mV    1.547V
20ns      1.251V     959.2mV    1.547V
[Rising Waveform]
R_fixture= 50.000
V_fixture= 1.800
V_fixture_min= 1.710
V_fixture_max= 1.890
|time   V(typ)   V(min)   V(max)
0s        515.2mV    792.2mV    332.7mV
643ps     515.2mV    792.2mV    341.4mV
828ps     515.3mV    792.2mV    1.717V
1.114ns   501.7mV    792.1mV    1.867V
1.456ns   1.606V     792.6mV    1.882V
1.72ns    1.772V     787.3mV    1.886V
1.995ns   1.786V     830.6mV    1.887V
2.487ns   1.794V     1.595V     1.889V
2.857ns   1.797V     1.694V     1.89V
20ns      1.8V       1.71V      1.89V
[Falling Waveform]
R_fixture= 50.000
V_fixture= 1.800
V_fixture_min= 1.710
V_fixture_max= 1.890
|time   V(typ)   V(min)   V(max)
0s        1.8V       1.71V      1.89V
724ps     1.8V       1.71V      1.953V
953ps     1.8V       1.71V      534.5mV
1.358ns   1.87V      1.71V      353.6mV
1.717ns   757.5mV    1.71V      341.2mV
2.153ns   548.7mV    1.712V     335.3mV
2.49ns    531.5mV    1.762V     333.5mV
3.117ns   521.6mV    932.9mV    332.9mV
3.84ns    517mV      816.4mV    332.7mV
20ns      515.2mV    792.2mV    332.7mV
[Falling Waveform]
R_fixture= 50.000
V_fixture= 0.0
V_fixture_min= 0.0
V_fixture_max= 0.0
|time   V(typ)   V(min)   V(max)
0s        1.251V     959.2mV    1.547V
688ps     1.251V     959.3mV    1.542V
849ps     1.251V     959.3mV    202.9mV
1.066ns   1.251V     959.3mV    24.74mV
1.278ns   1.2V       959.3mV    12.83mV
1.547ns   143.5mV    959.2mV    5.809mV
1.918ns   14.78mV    957.9mV    1.847mV
2.232ns   7.747mV    935.5mV    680uV
3.028ns   1.619mV    17.71mV    99.2uV
20ns      -80.19nV   94.51nV    8.513nV
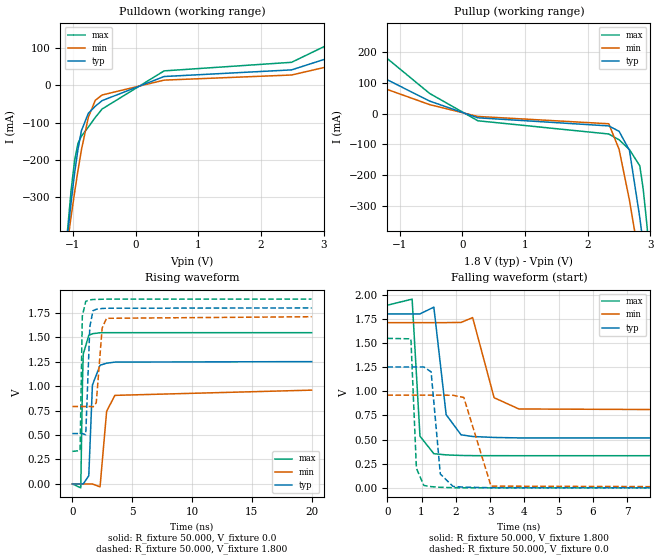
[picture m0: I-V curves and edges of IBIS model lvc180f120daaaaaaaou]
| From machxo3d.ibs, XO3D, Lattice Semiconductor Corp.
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|   Model lvc180f120daaaaaaaou
[Model] lvc180f120daaaaaaaou
Model_type Output
Polarity   Non-Inverting
Enable   Active-High
Vmeas =  0.900V
Cref =  0.0F
Rref =  1.000M
Vref =  0.0V
C_comp   4.200pF   3.800pF   7.500pF
[Temperature Range]   25.000   0.105k   -40.000
[Voltage Range]   1.800V   1.710V   1.890V
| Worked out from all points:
|   slope of the pulldown table from 0 to 0.27 V, typ, clamps not added: 16.9 ohm
|   slope of the pullup table from 0 to 0.27 V, typ, clamps not added: 18.2 ohm
|   rising waveform, R_fixture 50.000, V_fixture 0.0: 20-80 % time 255ps typ, 436ps min, 122ps max; typ from 0 V to 1.25 V
|   rising waveform, R_fixture 50.000, V_fixture 1.800: 20-80 % time 193ps typ, 340ps min, 91.1ps max; typ from 0.515 V to 1.8 V
|   falling waveform, R_fixture 50.000, V_fixture 1.800: 20-80 % time 238ps typ, 394ps min, 133ps max; typ from 1.8 V to 0.515 V
|   falling waveform, R_fixture 50.000, V_fixture 0.0: 20-80 % time 163ps typ, 291ps min, 87.2ps max; typ from 1.25 V to 0 V
[Pulldown]
|Voltage   I(typ)   I(min)   I(max)
-1.8V     -1.679A    -1.373A    -2.209A
-1.085V   -400.2mA   -419.6mA   -385.9mA
-1.03V    -314.7mA   -352.9mA   -282.2mA
-975mV    -236.9mA   -288.9mA   -202.9mA
-920mV    -171.5mA   -228.5mA   -155.5mA
-865mV    -121.8mA   -173.2mA   -136.5mA
-755mV    -75.11mA   -86.04mA   -112.3mA
-645mV    -56.28mA   -40.47mA   -86.59mA
-535mV    -41.11mA   -25.98mA   -63.61mA
455mV     23.63mA    13.95mA    38.77mA
2.49V     41.46mA    27.7mA     61.81mA
3.6V      101.5mA    70.82mA    152mA
[Pullup]
|Voltage   I(typ)   I(min)   I(max)
-1.8V     172.1mA    122.6mA    280.6mA
-525mV    40.92mA    29.37mA    65.88mA
245mV     -13.65mA   -9.247mA   -23.38mA
2.335V    -40.1mA    -33.12mA   -66.49mA
2.5V      -57.85mA   -116.8mA   -85.48mA
2.665V    -120mA     -282.7mA   -117.4mA
2.83V     -339mA     -482.1mA   -170.3mA
2.885V    -427.7mA   -552.2mA   -246.8mA
2.94V     -519.9mA   -623.4mA   -355.3mA
2.995V    -614.4mA   -695.6mA   -478.7mA
3.05V     -710.5mA   -768.5mA   -609.8mA
3.6V      -1.714A    -1.52A     -2.036A
[Ramp]
| variable   typ   min   max
dV/dt_r   0.751/0.254n   0.576/0.430n   0.928/0.121n
dV/dt_f   0.771/0.239n   0.551/0.394n   0.934/0.133n
R_load = 50.000
[Rising Waveform]
R_fixture= 50.000
V_fixture= 0.0
V_fixture_min= 0.0
V_fixture_max= 0.0
|time   V(typ)   V(min)   V(max)
0s        2.84nV     31.79nV    1.575nV
700ps     42.3uV     24.05uV    -40.15mV
842ps     39.46uV    24.05uV    1.041V
907ps     -125.1uV   -868.2nV   1.328V
1.369ns   83.75mV    151.8uV    1.52V
1.673ns   1.011V     -442uV     1.536V
2.311ns   1.214V     -30.03mV   1.546V
2.862ns   1.235V     743mV      1.547V
3.552ns   1.246V     905.8mV    1.547V
20ns      1.251V     959.2mV    1.547V
[Rising Waveform]
R_fixture= 50.000
V_fixture= 1.800
V_fixture_min= 1.710
V_fixture_max= 1.890
|time   V(typ)   V(min)   V(max)
0s        515.2mV    792.2mV    332.7mV
643ps     515.2mV    792.2mV    341.4mV
828ps     515.3mV    792.2mV    1.717V
1.114ns   501.7mV    792.1mV    1.867V
1.456ns   1.606V     792.6mV    1.882V
1.72ns    1.772V     787.3mV    1.886V
1.995ns   1.786V     830.6mV    1.887V
2.487ns   1.794V     1.595V     1.889V
2.857ns   1.797V     1.694V     1.89V
20ns      1.8V       1.71V      1.89V
[Falling Waveform]
R_fixture= 50.000
V_fixture= 1.800
V_fixture_min= 1.710
V_fixture_max= 1.890
|time   V(typ)   V(min)   V(max)
0s        1.8V       1.71V      1.89V
724ps     1.8V       1.71V      1.953V
953ps     1.8V       1.71V      534.5mV
1.358ns   1.87V      1.71V      353.6mV
1.717ns   757.5mV    1.71V      341.2mV
2.153ns   548.7mV    1.712V     335.3mV
2.49ns    531.5mV    1.762V     333.5mV
3.117ns   521.6mV    932.9mV    332.9mV
3.84ns    517mV      816.4mV    332.7mV
20ns      515.2mV    792.2mV    332.7mV
[Falling Waveform]
R_fixture= 50.000
V_fixture= 0.0
V_fixture_min= 0.0
V_fixture_max= 0.0
|time   V(typ)   V(min)   V(max)
0s        1.251V     959.2mV    1.547V
688ps     1.251V     959.3mV    1.542V
849ps     1.251V     959.3mV    202.9mV
1.066ns   1.251V     959.3mV    24.74mV
1.278ns   1.2V       959.3mV    12.83mV
1.547ns   143.5mV    959.2mV    5.809mV
1.918ns   14.78mV    957.9mV    1.847mV
2.232ns   7.747mV    935.5mV    680uV
3.028ns   1.619mV    17.71mV    99.2uV
20ns      -80.19nV   94.51nV    8.513nV
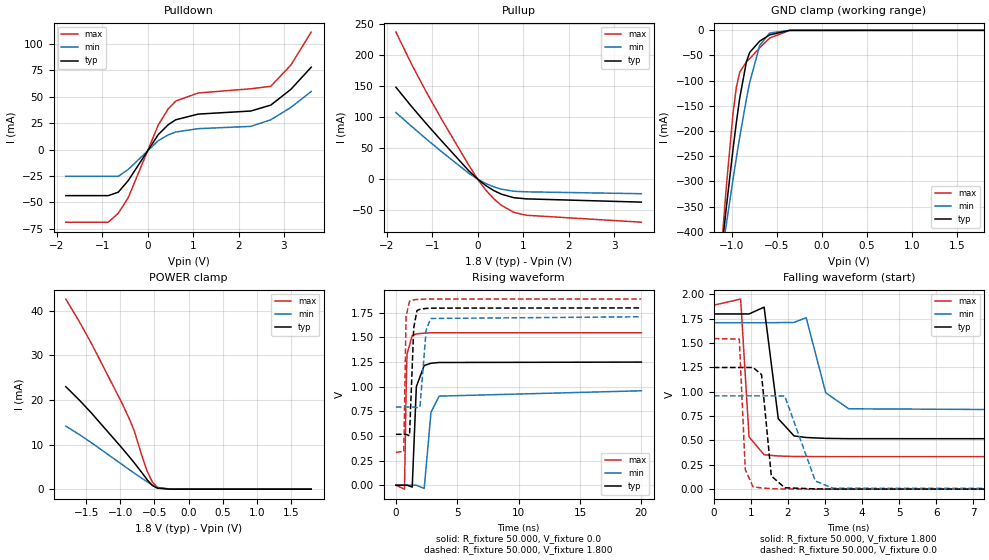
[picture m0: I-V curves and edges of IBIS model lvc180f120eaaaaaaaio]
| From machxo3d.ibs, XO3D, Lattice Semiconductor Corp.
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|   Model lvc180f120eaaaaaaaio
[Model] lvc180f120eaaaaaaaio
Model_type I/O
Polarity   Non-Inverting
Enable   Active-Low
Vinl =  0.630V
Vinh =  1.170V
Vmeas =  0.900V
Cref =  0.0F
Rref =  1.000M
Vref =  0.0V
C_comp   4.200pF   3.800pF   7.500pF
[Temperature Range]   25.000   0.105k   -40.000
[Voltage Range]   1.800V   1.710V   1.890V
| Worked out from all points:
|   slope of the pulldown table from 0 to 0.27 V, typ, clamps not added: 17 ohm
|   slope of the pullup table from 0 to 0.27 V, typ, clamps not added: 18.2 ohm
|   GND clamp passes 1 mA (typ) near -0.44 V on its own axis
|   POWER clamp passes 1 mA (typ) near -0.54 V on its own axis
|   rising waveform, R_fixture 50.000, V_fixture 0.0: 20-80 % time 251ps typ, 432ps min, 121ps max; typ from 0 V to 1.25 V
|   rising waveform, R_fixture 50.000, V_fixture 1.800: 20-80 % time 192ps typ, 340ps min, 90.8ps max; typ from 0.517 V to 1.8 V
|   falling waveform, R_fixture 50.000, V_fixture 1.800: 20-80 % time 238ps typ, 390ps min, 132ps max; typ from 1.8 V to 0.517 V
|   falling waveform, R_fixture 50.000, V_fixture 0.0: 20-80 % time 163ps typ, 292ps min, 87ps max; typ from 1.25 V to 0 V
[Pulldown]
|Voltage   I(typ)   I(min)   I(max)
-1.8V     -43.56mA   -25.31mA   -68.69mA
-865mV    -43.56mA   -25.31mA   -68.69mA
-645mV    -40.3mA    -25.31mA   -60.23mA
-425mV    -29.3mA    -18.76mA   -45.41mA
235mV     14.17mA    8.428mA    23.27mA
455mV     23.55mA    13.92mA    38.6mA
620mV     28.2mA     16.61mA    45.89mA
1.115V    33.55mA    19.77mA    53.52mA
2.27V     36.44mA    21.92mA    57.47mA
2.71V     42.06mA    28.16mA    59.85mA
3.15V     56.84mA    39.76mA    79.78mA
3.6V      77.9mA     54.93mA    111.1mA
[Pullup]
|Voltage   I(typ)   I(min)   I(max)
-1.8V     148.4mA    107.6mA    237.4mA
-1.46V    117.7mA    85.64mA    186.2mA
-1.13V    89.39mA    64.79mA    140.5mA
-800mV    62.24mA    44.68mA    97.43mA
-195mV    13.45mA    9.406mA    22.28mA
25mV      -1.58mA    -1.08mA    -2.674mA
190mV     -10.93mA   -7.424mA   -18.66mA
355mV     -18.44mA   -12.42mA   -31.8mA
520mV     -24.17mA   -16.11mA   -42.18mA
795mV     -29.88mA   -19.49mA   -53.5mA
1.07V     -31.75mA   -20.4mA    -58.22mA
3.6V      -37.02mA   -23.42mA   -69.39mA
[GND_clamp]
|Voltage   I(typ)   I(min)   I(max)
-1.8V     -1.677A    -1.372A    -2.207A
-1.097V   -411.6mA   -430.5mA   -392.9mA
-1.06V    -351mA     -384.7mA   -309.8mA
-986mV    -235.9mA   -295.9mA   -164.7mA
-949mV    -183mA     -253.4mA   -113mA
-912mV    -135mA     -212.5mA   -83.33mA
-838mV    -63.16mA   -137.2mA   -62.66mA
-801mV    -43.93mA   -103.8mA   -56.25mA
-690mV    -21.49mA   -30.06mA   -34.72mA
-579mV    -9.043mA   -5.343mA   -15.31mA
-357mV    -110.3uA   -52.32uA   -166.6uA
1.8V      0A         0A         0A
[POWER_clamp]
|Voltage   I(typ)   I(min)   I(max)
-1.8V     22.96mA    14.12mA    42.58mA
-1.604V   19.99mA    12.25mA    37.59mA
-1.419V   16.97mA    10.35mA    32.49mA
-975mV    9.199mA    5.527mA    19.24mA
-864mV    7.174mA    4.324mA    15.6mA
-790mV    5.788mA    3.534mA    12.79mA
-679mV    3.605mA    2.374mA    7.249mA
-605mV    2.066mA    1.631mA    3.958mA
-531mV    820.6uA    942.6uA    1.61mA
-457mV    221.3uA    381uA      405.2uA
-272mV    4.708uA    6.259uA    4.369uA
1.8V      0A         0A         4.229nA
[Ramp]
| variable   typ   min   max
dV/dt_r   0.750/0.252n   0.575/0.427n   0.928/0.120n
dV/dt_f   0.770/0.237n   0.550/0.391n   0.933/0.132n
R_load = 50.000
[Rising Waveform]
R_fixture= 50.000
V_fixture= 0.0
V_fixture_min= 0.0
V_fixture_max= 0.0
|time   V(typ)   V(min)   V(max)
0s        2.942nV    32.1nV     1.699nV
700ps     42.3uV     24.11uV    -40.27mV
843ps     40.89uV    24.11uV    1.049V
907ps     -117.7uV   -831.7nV   1.33V
1.328ns   -19.19mV   116.3uV    1.52V
1.665ns   1.002V     -436.7uV   1.536V
2.305ns   1.216V     -32.69mV   1.545V
2.859ns   1.238V     742mV      1.547V
3.521ns   1.246V     904.6mV    1.547V
20ns      1.25V      958.6mV    1.547V
[Rising Waveform]
R_fixture= 50.000
V_fixture= 1.800
V_fixture_min= 1.710
V_fixture_max= 1.890
|time   V(typ)   V(min)   V(max)
0s        516.8mV    793.5mV    334.2mV
643ps     516.8mV    793.5mV    343.1mV
827ps     516.9mV    793.5mV    1.716V
1.108ns   501.7mV    793.4mV    1.869V
1.453ns   1.601V     793.9mV    1.882V
1.72ns    1.774V     788.6mV    1.886V
1.962ns   1.786V     798mV      1.888V
2.463ns   1.795V     1.575V     1.89V
2.835ns   1.798V     1.693V     1.89V
20ns      1.8V       1.71V      1.89V
[Falling Waveform]
R_fixture= 50.000
V_fixture= 1.800
V_fixture_min= 1.710
V_fixture_max= 1.890
|time   V(typ)   V(min)   V(max)
0s        1.8V       1.71V      1.89V
724ps     1.8V       1.71V      1.953V
951ps     1.8V       1.71V      537.4mV
1.357ns   1.87V      1.71V      353.1mV
1.739ns   724mV      1.711V     340.9mV
2.164ns   547mV      1.713V     336mV
2.49ns    530.7mV    1.762V     334.9mV
3.019ns   521.8mV    989.6mV    334.4mV
3.639ns   518.7mV    825.9mV    334.2mV
20ns      516.8mV    793.5mV    334.2mV
[Falling Waveform]
R_fixture= 50.000
V_fixture= 0.0
V_fixture_min= 0.0
V_fixture_max= 0.0
|time   V(typ)   V(min)   V(max)
0s        1.25V      958.6mV    1.547V
688ps     1.25V      958.6mV    1.542V
849ps     1.25V      958.6mV    201.4mV
1.058ns   1.25V      958.6mV    24.92mV
1.288ns   1.177V     958.6mV    12.44mV
1.551ns   135.8mV    958.6mV    5.224mV
1.913ns   14.52mV    957.2mV    1.671mV
2.738ns   2.735mV    84.29mV    194.5uV
3.206ns   986.9uV    10.33mV    64.15uV
20ns      -219.1nV   -3.755nV   -88.11nV
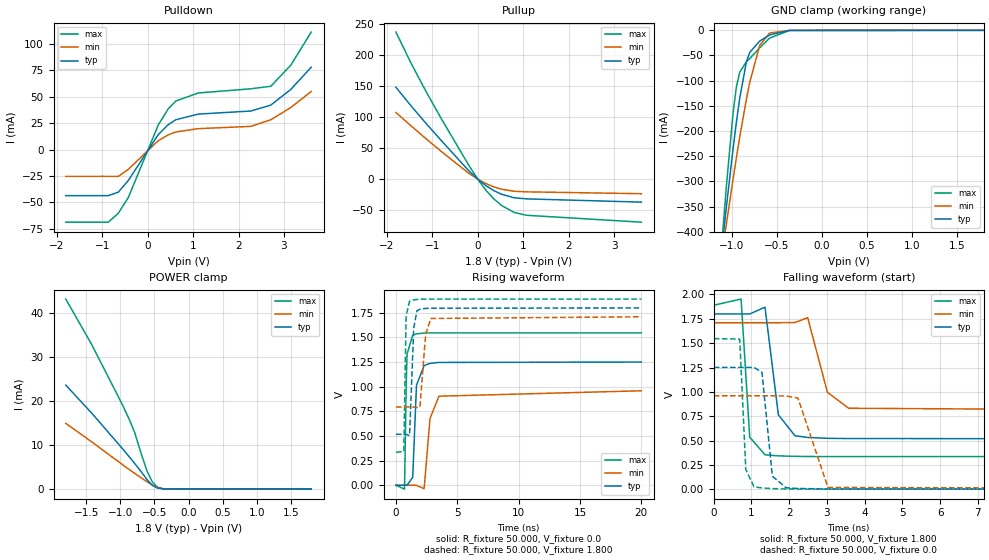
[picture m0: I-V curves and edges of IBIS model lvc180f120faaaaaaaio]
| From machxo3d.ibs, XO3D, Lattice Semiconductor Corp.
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|   Model lvc180f120faaaaaaaio
[Model] lvc180f120faaaaaaaio
Model_type I/O
Polarity   Non-Inverting
Enable   Active-Low
Vinl =  0.630V
Vinh =  1.170V
Vmeas =  0.900V
Cref =  0.0F
Rref =  1.000M
Vref =  0.0V
C_comp   4.200pF   3.800pF   7.500pF
[Temperature Range]   25.000   0.105k   -40.000
[Voltage Range]   1.800V   1.710V   1.890V
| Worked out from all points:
|   slope of the pulldown table from 0 to 0.27 V, typ, clamps not added: 17 ohm
|   slope of the pullup table from 0 to 0.27 V, typ, clamps not added: 18.2 ohm
|   GND clamp passes 1 mA (typ) near -0.44 V on its own axis
|   POWER clamp passes 1 mA (typ) near -0.54 V on its own axis
|   rising waveform, R_fixture 50.000, V_fixture 0.0: 20-80 % time 252ps typ, 431ps min, 121ps max; typ from 0 V to 1.25 V
|   rising waveform, R_fixture 50.000, V_fixture 1.800: 20-80 % time 192ps typ, 339ps min, 90.7ps max; typ from 0.518 V to 1.8 V
|   falling waveform, R_fixture 50.000, V_fixture 1.800: 20-80 % time 236ps typ, 391ps min, 133ps max; typ from 1.8 V to 0.518 V
|   falling waveform, R_fixture 50.000, V_fixture 0.0: 20-80 % time 163ps typ, 291ps min, 87.1ps max; typ from 1.25 V to 0 V
[Pulldown]
|Voltage   I(typ)   I(min)   I(max)
-1.8V     -43.56mA   -25.31mA   -68.69mA
-865mV    -43.56mA   -25.31mA   -68.69mA
-645mV    -40.3mA    -25.31mA   -60.23mA
-425mV    -29.3mA    -18.76mA   -45.41mA
235mV     14.17mA    8.428mA    23.27mA
455mV     23.55mA    13.92mA    38.6mA
620mV     28.2mA     16.61mA    45.89mA
1.115V    33.55mA    19.77mA    53.52mA
2.27V     36.44mA    21.92mA    57.47mA
2.71V     42.06mA    28.16mA    59.84mA
3.15V     56.83mA    39.76mA    79.77mA
3.6V      77.88mA    54.94mA    111.1mA
[Pullup]
|Voltage   I(typ)   I(min)   I(max)
-1.8V     148.4mA    107.6mA    237.4mA
-1.46V    117.7mA    85.66mA    186.2mA
-1.13V    89.39mA    64.8mA     140.5mA
-800mV    62.24mA    44.68mA    97.43mA
-195mV    13.45mA    9.406mA    22.28mA
25mV      -1.58mA    -1.08mA    -2.674mA
190mV     -10.93mA   -7.424mA   -18.66mA
355mV     -18.44mA   -12.42mA   -31.8mA
520mV     -24.17mA   -16.11mA   -42.18mA
795mV     -29.88mA   -19.49mA   -53.5mA
1.07V     -31.75mA   -20.4mA    -58.22mA
3.6V      -37.02mA   -23.42mA   -69.39mA
[GND_clamp]
|Voltage   I(typ)   I(min)   I(max)
-1.8V     -1.677A    -1.372A    -2.207A
-1.097V   -411.6mA   -430.5mA   -393mA
-1.06V    -351mA     -384.7mA   -309.9mA
-986mV    -235.9mA   -295.9mA   -164.7mA
-949mV    -183mA     -253.4mA   -113mA
-912mV    -135mA     -212.5mA   -83.35mA
-838mV    -63.17mA   -137.2mA   -62.69mA
-801mV    -43.94mA   -103.8mA   -56.28mA
-690mV    -21.51mA   -30.07mA   -34.75mA
-579mV    -9.065mA   -5.356mA   -15.35mA
-357mV    -147.5uA   -72.3uA    -237.1uA
1.8V      -12.41nA   0A         -10.91uA
[POWER_clamp]
|Voltage   I(typ)   I(min)   I(max)
-1.8V     23.65mA    14.95mA    43.22mA
-1.419V   17.27mA    10.75mA    32.84mA
-975mV    9.322mA    5.649mA    19.37mA
-864mV    7.265mA    4.408mA    15.69mA
-790mV    5.86mA     3.598mA    12.87mA
-679mV    3.655mA    2.417mA    7.32mA
-605mV    2.107mA    1.665mA    4.016mA
-531mV    854uA      968.7uA    1.658mA
-457mV    251.6uA    402uA      448.6uA
-383mV    77.17uA    103.3uA    115.3uA
-235mV    19.9uA     13.46uA    32.69uA
1.8V      0A         0A         0A
[Ramp]
| variable   typ   min   max
dV/dt_r   0.750/0.252n   0.575/0.427n   0.928/0.120n
dV/dt_f   0.769/0.237n   0.549/0.392n   0.933/0.133n
R_load = 50.000
[Rising Waveform]
R_fixture= 50.000
V_fixture= 0.0
V_fixture_min= 0.0
V_fixture_max= 0.0
|time   V(typ)   V(min)   V(max)
0s        437uV      326.8uV    605.6uV
700ps     478.7uV    350.6uV    -39.23mV
842ps     486.1uV    350.6uV    1.044V
907ps     321.9uV    350.6uV    1.331V
1.368ns   81.37mV    476.1uV    1.523V
1.675ns   1.016V     -93.68uV   1.537V
2.299ns   1.216V     -34.2mV    1.545V
2.777ns   1.237V     678.6mV    1.547V
3.508ns   1.247V     904.4mV    1.547V
20ns      1.251V     959.2mV    1.547V
[Rising Waveform]
R_fixture= 50.000
V_fixture= 1.800
V_fixture_min= 1.710
V_fixture_max= 1.890
|time   V(typ)   V(min)   V(max)
0s        517.6mV    794.2mV    335.1mV
643ps     517.6mV    794.2mV    344.1mV
827ps     518mV      794.2mV    1.717V
1.112ns   503.4mV    794.2mV    1.869V
1.451ns   1.596V     794.7mV    1.882V
1.72ns    1.773V     789.3mV    1.886V
1.958ns   1.786V     795.5mV    1.888V
2.422ns   1.795V     1.531V     1.889V
2.838ns   1.797V     1.693V     1.89V
20ns      1.8V       1.71V      1.89V
[Falling Waveform]
R_fixture= 50.000
V_fixture= 1.800
V_fixture_min= 1.710
V_fixture_max= 1.890
|time   V(typ)   V(min)   V(max)
0s        1.8V       1.71V      1.89V
724ps     1.8V       1.71V      1.953V
953ps     1.8V       1.71V      534.5mV
1.358ns   1.87V      1.71V      353.6mV
1.713ns   763.8mV    1.71V      342.3mV
2.153ns   548.7mV    1.712V     337.4mV
2.49ns    531.5mV    1.762V     335.7mV
3.013ns   522.9mV    995.3mV    335.3mV
3.579ns   519.9mV    831.4mV    335.2mV
20ns      517.5mV    794.2mV    335.1mV
[Falling Waveform]
R_fixture= 50.000
V_fixture= 0.0
V_fixture_min= 0.0
V_fixture_max= 0.0
|time   V(typ)   V(min)   V(max)
0s        1.251V     959.2mV    1.547V
688ps     1.251V     959.3mV    1.542V
849ps     1.251V     959.3mV    202.9mV
1.066ns   1.251V     959.3mV    24.74mV
1.278ns   1.2V       959.3mV    12.83mV
1.553ns   133.7mV    959.2mV    5.774mV
1.918ns   14.78mV    957.9mV    2.237mV
2.232ns   7.747mV    935.5mV    1.323mV
3.028ns   1.894mV    17.71mV    719.7uV
20ns      436.9uV    326.8uV    605.4uV
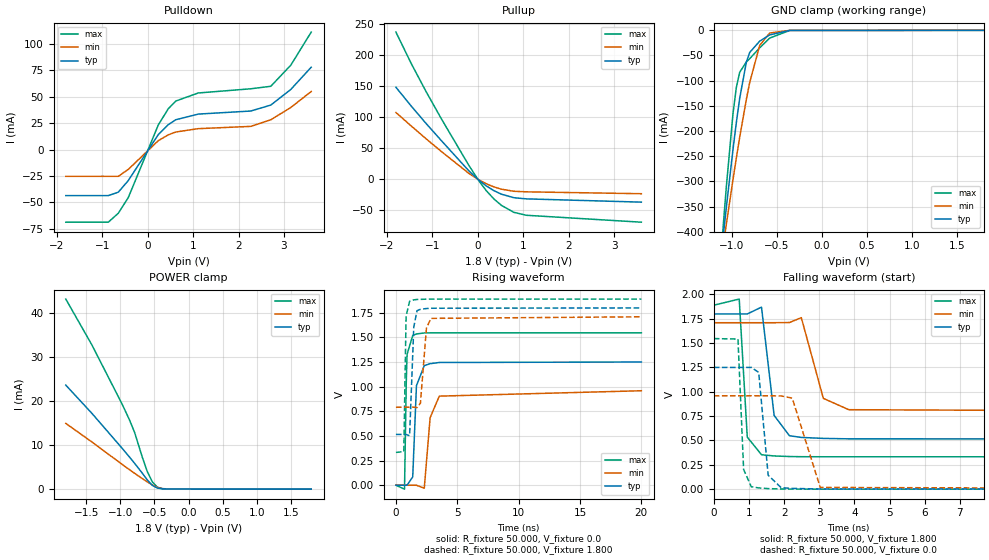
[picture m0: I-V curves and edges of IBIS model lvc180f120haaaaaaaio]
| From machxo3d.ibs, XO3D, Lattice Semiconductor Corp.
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|   Model lvc180f120haaaaaaaio
[Model] lvc180f120haaaaaaaio
Model_type I/O
Polarity   Non-Inverting
Enable   Active-Low
Vinl =  0.630V
Vinh =  1.170V
Vmeas =  0.900V
Cref =  0.0F
Rref =  1.000M
Vref =  0.0V
C_comp   4.200pF   3.800pF   7.500pF
[Temperature Range]   25.000   0.105k   -40.000
[Voltage Range]   1.800V   1.710V   1.890V
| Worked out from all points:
|   slope of the pulldown table from 0 to 0.27 V, typ, clamps not added: 17 ohm
|   slope of the pullup table from 0 to 0.27 V, typ, clamps not added: 18.2 ohm
|   GND clamp passes 1 mA (typ) near -0.44 V on its own axis
|   POWER clamp passes 1 mA (typ) near -0.54 V on its own axis
|   rising waveform, R_fixture 50.000, V_fixture 0.0: 20-80 % time 255ps typ, 436ps min, 122ps max; typ from 0 V to 1.25 V
|   rising waveform, R_fixture 50.000, V_fixture 1.800: 20-80 % time 193ps typ, 340ps min, 91.1ps max; typ from 0.515 V to 1.8 V
|   falling waveform, R_fixture 50.000, V_fixture 1.800: 20-80 % time 238ps typ, 394ps min, 133ps max; typ from 1.8 V to 0.515 V
|   falling waveform, R_fixture 50.000, V_fixture 0.0: 20-80 % time 163ps typ, 291ps min, 87.2ps max; typ from 1.25 V to 0 V
[Pulldown]
|Voltage   I(typ)   I(min)   I(max)
-1.8V     -43.56mA   -25.31mA   -68.69mA
-865mV    -43.56mA   -25.31mA   -68.69mA
-645mV    -40.3mA    -25.31mA   -60.23mA
-425mV    -29.3mA    -18.76mA   -45.41mA
235mV     14.17mA    8.428mA    23.27mA
455mV     23.55mA    13.92mA    38.6mA
620mV     28.2mA     16.61mA    45.89mA
1.115V    33.55mA    19.77mA    53.52mA
2.27V     36.44mA    21.92mA    57.47mA
2.71V     42.06mA    28.16mA    59.84mA
3.15V     56.83mA    39.76mA    79.77mA
3.6V      77.88mA    54.94mA    111.1mA
[Pullup]
|Voltage   I(typ)   I(min)   I(max)
-1.8V     148.4mA    107.6mA    237.4mA
-1.46V    117.7mA    85.66mA    186.2mA
-1.13V    89.39mA    64.8mA     140.5mA
-800mV    62.24mA    44.68mA    97.43mA
-195mV    13.45mA    9.406mA    22.28mA
25mV      -1.58mA    -1.08mA    -2.674mA
190mV     -10.93mA   -7.424mA   -18.66mA
355mV     -18.44mA   -12.42mA   -31.8mA
520mV     -24.17mA   -16.11mA   -42.18mA
795mV     -29.88mA   -19.49mA   -53.5mA
1.07V     -31.75mA   -20.4mA    -58.22mA
3.6V      -37.02mA   -23.42mA   -69.38mA
[GND_clamp]
|Voltage   I(typ)   I(min)   I(max)
-1.8V     -1.677A    -1.372A    -2.207A
-1.097V   -411.7mA   -430.5mA   -393mA
-1.06V    -351mA     -384.7mA   -309.9mA
-986mV    -235.9mA   -295.9mA   -164.8mA
-949mV    -183mA     -253.4mA   -113.1mA
-912mV    -135mA     -212.5mA   -83.39mA
-838mV    -63.2mA    -137.2mA   -62.73mA
-801mV    -43.97mA   -103.8mA   -56.32mA
-690mV    -21.54mA   -30.09mA   -34.79mA
-579mV    -9.102mA   -5.388mA   -15.4mA
-357mV    -191.3uA   -96.81uA   -298.1uA
1.8V      -12.41nA   0A         -10.91uA
[POWER_clamp]
|Voltage   I(typ)   I(min)   I(max)
-1.8V     23.65mA    14.95mA    43.22mA
-1.419V   17.27mA    10.75mA    32.84mA
-975mV    9.322mA    5.649mA    19.37mA
-864mV    7.265mA    4.408mA    15.69mA
-790mV    5.86mA     3.598mA    12.87mA
-679mV    3.655mA    2.417mA    7.32mA
-605mV    2.107mA    1.665mA    4.016mA
-531mV    854uA      968.7uA    1.658mA
-457mV    251.6uA    402uA      448.6uA
-383mV    77.17uA    103.3uA    115.3uA
-235mV    19.9uA     13.46uA    32.69uA
1.8V      0A         0A         0A
[Ramp]
| variable   typ   min   max
dV/dt_r   0.751/0.254n   0.576/0.430n   0.928/0.121n
dV/dt_f   0.771/0.239n   0.551/0.394n   0.934/0.133n
R_load = 50.000
[Rising Waveform]
R_fixture= 50.000
V_fixture= 0.0
V_fixture_min= 0.0
V_fixture_max= 0.0
|time   V(typ)   V(min)   V(max)
0s        2.84nV     31.79nV    1.575nV
700ps     42.3uV     24.05uV    -40.15mV
842ps     39.46uV    24.05uV    1.041V
907ps     -125.1uV   -867.6nV   1.328V
1.369ns   83.75mV    151.8uV    1.52V
1.673ns   1.011V     -442uV     1.536V
2.311ns   1.214V     -30.03mV   1.546V
2.786ns   1.234V     685.1mV    1.547V
3.535ns   1.246V     904.5mV    1.547V
20ns      1.251V     959.2mV    1.547V
[Rising Waveform]
R_fixture= 50.000
V_fixture= 1.800
V_fixture_min= 1.710
V_fixture_max= 1.890
|time   V(typ)   V(min)   V(max)
0s        515.2mV    792.2mV    332.7mV
643ps     515.2mV    792.2mV    341.4mV
828ps     515.3mV    792.2mV    1.717V
1.114ns   501.7mV    792.1mV    1.867V
1.456ns   1.606V     792.6mV    1.882V
1.72ns    1.772V     787.3mV    1.886V
1.996ns   1.786V     831.8mV    1.887V
2.487ns   1.794V     1.595V     1.889V
2.857ns   1.797V     1.694V     1.89V
20ns      1.8V       1.71V      1.89V
[Falling Waveform]
R_fixture= 50.000
V_fixture= 1.800
V_fixture_min= 1.710
V_fixture_max= 1.890
|time   V(typ)   V(min)   V(max)
0s        1.8V       1.71V      1.89V
724ps     1.8V       1.71V      1.953V
953ps     1.8V       1.71V      534.5mV
1.358ns   1.87V      1.71V      353.6mV
1.717ns   757.5mV    1.71V      341.2mV
2.153ns   548.7mV    1.712V     335.3mV
2.49ns    531.5mV    1.762V     333.5mV
3.117ns   521.6mV    932.9mV    332.9mV
3.84ns    517mV      816.4mV    332.7mV
20ns      515.2mV    792.2mV    332.7mV
[Falling Waveform]
R_fixture= 50.000
V_fixture= 0.0
V_fixture_min= 0.0
V_fixture_max= 0.0
|time   V(typ)   V(min)   V(max)
0s        1.251V     959.2mV    1.547V
688ps     1.251V     959.3mV    1.542V
849ps     1.251V     959.3mV    202.9mV
1.066ns   1.251V     959.3mV    24.74mV
1.278ns   1.2V       959.3mV    12.83mV
1.547ns   143.5mV    959.2mV    5.809mV
1.918ns   14.78mV    957.9mV    1.847mV
2.232ns   7.747mV    935.5mV    680uV
3.028ns   1.619mV    17.71mV    99.2uV
20ns      -80.19nV   -4.598nV   8.513nV
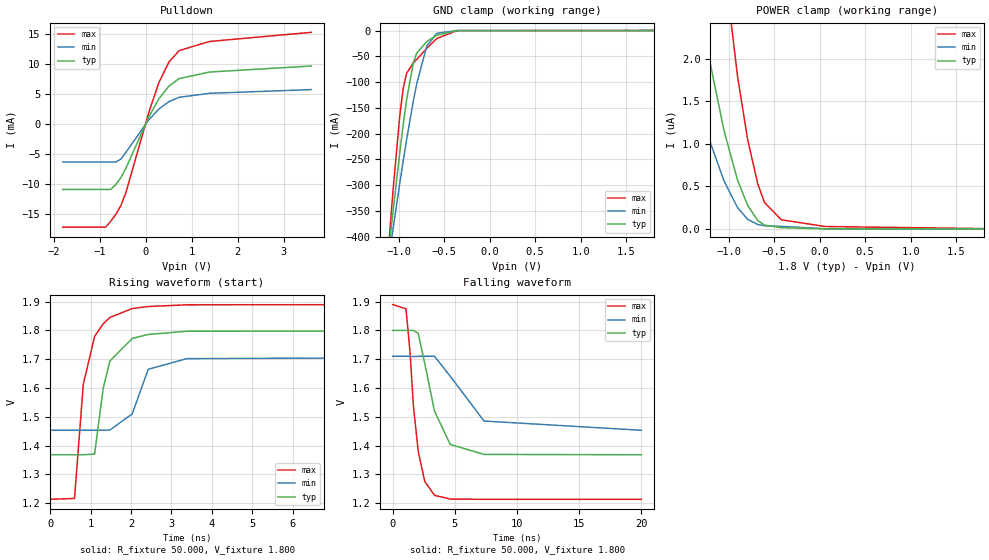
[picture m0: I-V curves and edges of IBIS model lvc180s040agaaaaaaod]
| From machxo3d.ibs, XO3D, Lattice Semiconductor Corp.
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|   Model lvc180s040agaaaaaaod
[Model] lvc180s040agaaaaaaod
Model_type I/O_open_drain
Polarity   Non-Inverting
Enable   Active-Low
Vinl =  0.630V
Vinh =  1.170V
Vmeas =  0.900V
Cref =  0.0F
Rref = 10.00k
Vref = 1.80V
C_comp   4.200pF   3.800pF   7.500pF
[Temperature Range]   25.000   0.105k   -40.000
[Voltage Range]   1.800V   1.710V   1.890V
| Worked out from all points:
|   slope of the pulldown table from 0 to 0.27 V, typ, clamps not added: 68 ohm
|   GND clamp passes 1 mA (typ) near -0.44 V on its own axis
|   rising waveform, R_fixture 50.000, V_fixture 1.800: 20-80 % time 354ps typ, 367ps min, 354ps max; typ from 1.37 V to 1.8 V
|   falling waveform, R_fixture 50.000, V_fixture 1.800: 20-80 % time 1.4ns typ, 2.29ns min, 864ps max; typ from 1.8 V to 1.37 V
[Pulldown]
|Voltage   I(typ)   I(min)   I(max)
-1.8V     -10.89mA   -6.327mA   -17.17mA
-865mV    -10.89mA   -6.327mA   -17.17mA
-755mV    -10.89mA   -6.327mA   -16.17mA
-645mV    -10.07mA   -6.327mA   -15.06mA
-535mV    -8.903mA   -5.829mA   -13.55mA
-425mV    -7.325mA   -4.689mA   -11.35mA
70mV      1.17mA     698.5uA    1.923mA
290mV     4.214mA    2.504mA    6.922mA
510mV     6.332mA    3.737mA    10.36mA
730mV     7.558mA    4.447mA    12.22mA
1.39V     8.652mA    5.109mA    13.74mA
3.6V      9.654mA    5.728mA    15.26mA
[GND_clamp]
|Voltage   I(typ)   I(min)   I(max)
-1.8V     -1.677A    -1.372A    -2.207A
-1.097V   -411.6mA   -430.5mA   -392.9mA
-1.06V    -351mA     -384.7mA   -309.8mA
-986mV    -235.9mA   -295.9mA   -164.7mA
-949mV    -183mA     -253.4mA   -113mA
-912mV    -135mA     -212.5mA   -83.33mA
-838mV    -63.16mA   -137.2mA   -62.66mA
-801mV    -43.93mA   -103.8mA   -56.25mA
-690mV    -21.49mA   -30.06mA   -34.72mA
-579mV    -9.043mA   -5.343mA   -15.31mA
-357mV    -110.3uA   -52.32uA   -166.6uA
1.8V      0A         0A         0A
[POWER_clamp]
|Voltage   I(typ)   I(min)   I(max)
-1.8V     6.918uA    4.075uA    15.53uA
-1.641V   5.335uA    3.081uA    12.17uA
-1.382V   3.16uA     1.741uA    7.507uA
-1.197V   1.931uA    1.01uA     4.843uA
-1.049V   1.156uA    564.3nA    3.128uA
-901mV    576.3nA    251.8nA    1.796uA
-790mV    276.2nA    113.3nA    1.051uA
-679mV    99.59nA    51.82nA    530.4nA
-605mV    45.38nA    37.94nA    310.9nA
-420mV    15.41nA    30.13nA    108.3nA
61mV      1.594nA    2.49nA     28.82nA
1.8V      0A         0A         4.229nA
[Ramp]
| variable   typ   min   max
dV/dt_r   0.259/0.351n   0.154/0.364n   0.406/0.353n
dV/dt_f   0.259/1.414n   0.154/2.267n   0.406/0.856n
R_load = 50.000
[Rising Waveform]
R_fixture= 50.000
V_fixture= 1.800
V_fixture_min= 1.710
V_fixture_max= 1.890
|time   V(typ)   V(min)   V(max)
0s        1.368V     1.453V     1.213V
600ps     1.368V     1.453V     1.216V
817ps     1.368V     1.453V     1.612V
1.097ns   1.37V      1.453V     1.779V
1.31ns    1.599V     1.453V     1.823V
1.477ns   1.694V     1.454V     1.845V
2.029ns   1.772V     1.51V      1.876V
2.425ns   1.786V     1.665V     1.883V
3.385ns   1.797V     1.702V     1.889V
20ns      1.8V       1.71V      1.89V
[Falling Waveform]
R_fixture= 50.000
V_fixture= 1.800
V_fixture_min= 1.710
V_fixture_max= 1.890
|time   V(typ)   V(min)   V(max)
0s        1.8V       1.71V      1.89V
1.068ns   1.8V       1.71V      1.875V
1.392ns   1.8V       1.71V      1.726V
1.666ns   1.8V       1.709V     1.537V
2.047ns   1.79V      1.71V      1.381V
2.58ns    1.685V     1.71V      1.275V
3.361ns   1.52V      1.71V      1.227V
4.623ns   1.404V     1.641V     1.214V
7.347ns   1.369V     1.485V     1.213V
20ns      1.368V     1.453V     1.213V
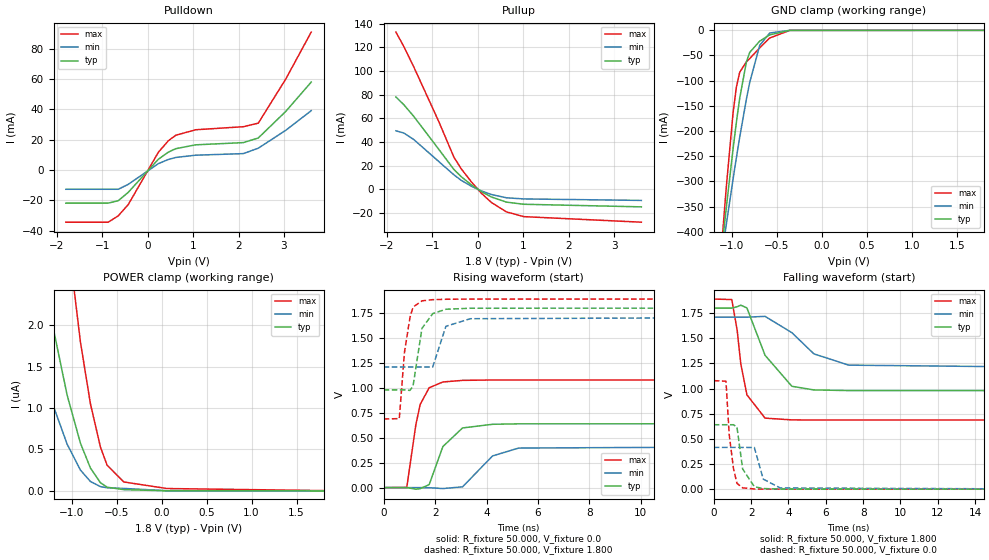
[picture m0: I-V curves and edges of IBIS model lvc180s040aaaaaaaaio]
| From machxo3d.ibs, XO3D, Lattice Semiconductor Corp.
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|   Model lvc180s040aaaaaaaaio
[Model] lvc180s040aaaaaaaaio
Model_type I/O
Polarity   Non-Inverting
Enable   Active-Low
Vinl =  0.630V
Vinh =  1.170V
Vmeas =  0.900V
Cref =  0.0F
Rref =  1.000M
Vref =  0.0V
C_comp   4.200pF   3.800pF   7.500pF
[Temperature Range]   25.000   0.105k   -40.000
[Voltage Range]   1.800V   1.710V   1.890V
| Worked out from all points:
|   slope of the pulldown table from 0 to 0.27 V, typ, clamps not added: 34 ohm
|   slope of the pullup table from 0 to 0.27 V, typ, clamps not added: 45.6 ohm
|   GND clamp passes 1 mA (typ) near -0.44 V on its own axis
|   rising waveform, R_fixture 50.000, V_fixture 0.0: 20-80 % time 622ps typ, 949ps min, 414ps max; typ from 0 V to 0.641 V
|   rising waveform, R_fixture 50.000, V_fixture 1.800: 20-80 % time 363ps typ, 366ps min, 304ps max; typ from 0.98 V to 1.8 V
|   falling waveform, R_fixture 50.000, V_fixture 1.800: 20-80 % time 1.1ns typ, 1.77ns min, 622ps max; typ from 1.8 V to 0.98 V
|   falling waveform, R_fixture 50.000, V_fixture 0.0: 20-80 % time 386ps typ, 403ps min, 324ps max; typ from 0.641 V to 0 V
[Pulldown]
|Voltage   I(typ)   I(min)   I(max)
-1.8V     -21.78mA   -12.65mA   -34.34mA
-865mV    -21.78mA   -12.65mA   -34.34mA
-645mV    -20.15mA   -12.65mA   -30.11mA
-425mV    -14.65mA   -9.378mA   -22.7mA
235mV     7.083mA    4.214mA    11.64mA
455mV     11.78mA    6.962mA    19.3mA
620mV     14.1mA     8.304mA    22.95mA
1.06V     16.63mA    9.799mA    26.56mA
2.105V    18.09mA    10.84mA    28.56mA
2.435V    21.14mA    14.41mA    30.89mA
3.04V     38.65mA    26.21mA    59.99mA
3.6V      57.96mA    39.13mA    90.9mA
[Pullup]
|Voltage   I(typ)   I(min)   I(max)
-1.8V     77.99mA    49.41mA    132.8mA
-1.625V   71.39mA    47.54mA    120.5mA
-1.405V   61.49mA    41.97mA    103.2mA
-855mV    33.69mA    23.41mA    57.06mA
-525mV    16.8mA     12.27mA    27.21mA
-360mV    10.56mA    7.514mA    17.17mA
-140mV    3.787mA    2.633mA    6.305mA
80mV      -1.961mA   -1.338mA   -3.329mA
300mV     -6.456mA   -4.362mA   -11.09mA
630mV     -10.81mA   -7.147mA   -19.03mA
1.015V    -12.62mA   -8.118mA   -23.07mA
3.6V      -14.81mA   -9.369mA   -27.76mA
[GND_clamp]
|Voltage   I(typ)   I(min)   I(max)
-1.8V     -1.677A    -1.372A    -2.207A
-1.097V   -411.6mA   -430.5mA   -392.9mA
-1.06V    -351mA     -384.7mA   -309.8mA
-986mV    -235.9mA   -295.9mA   -164.7mA
-949mV    -183mA     -253.4mA   -113mA
-912mV    -135mA     -212.5mA   -83.33mA
-838mV    -63.16mA   -137.2mA   -62.66mA
-801mV    -43.93mA   -103.8mA   -56.25mA
-690mV    -21.49mA   -30.06mA   -34.72mA
-579mV    -9.043mA   -5.343mA   -15.31mA
-357mV    -110.3uA   -52.32uA   -166.6uA
1.8V      0A         0A         0A
[POWER_clamp]
|Voltage   I(typ)   I(min)   I(max)
-1.8V     6.918uA    4.075uA    15.53uA
-1.641V   5.335uA    3.081uA    12.17uA
-1.382V   3.16uA     1.741uA    7.507uA
-1.197V   1.931uA    1.01uA     4.843uA
-1.049V   1.156uA    564.3nA    3.128uA
-901mV    576.3nA    251.8nA    1.796uA
-790mV    276.2nA    113.3nA    1.051uA
-679mV    99.59nA    51.82nA    530.4nA
-605mV    45.38nA    37.94nA    310.9nA
-420mV    15.41nA    30.13nA    108.2nA
61mV      1.594nA    2.49nA     28.82nA
1.8V      0A         0A         4.229nA
[Ramp]
| variable   typ   min   max
dV/dt_r   0.384/0.627n   0.249/0.943n   0.647/0.409n
dV/dt_f   0.492/1.088n   0.301/1.765n   0.721/0.622n
R_load = 50.000
[Rising Waveform]
R_fixture= 50.000
V_fixture= 0.0
V_fixture_min= 0.0
V_fixture_max= 0.0
|time   V(typ)   V(min)   V(max)
0s        4.812nV    48.48nV    2.958nV
899ps     115.7uV    2.148uV    2.376mV
1.252ns   -15.47mV   117uV      630.1mV
1.419ns   -10.69mV   296.3uV    833.3mV
1.77ns    30.08mV    -898.4uV   1.001V
2.303ns   411.9mV    -9.352mV   1.059V
3.067ns   598.2mV    7.636mV    1.075V
4.234ns   634.8mV    317.7mV    1.079V
5.248ns   639.4mV    396.6mV    1.079V
20ns      640.6mV    415.2mV    1.079V
[Rising Waveform]
R_fixture= 50.000
V_fixture= 1.800
V_fixture_min= 1.710
V_fixture_max= 1.890
|time   V(typ)   V(min)   V(max)
0s        979.8mV    1.209V     687.7mV
608ps     979.8mV    1.209V     691.8mV
809ps     979.8mV    1.209V     1.356V
1.024ns   974.3mV    1.209V     1.707V
1.143ns   1.018V     1.209V     1.809V
1.489ns   1.596V     1.209V     1.872V
1.907ns   1.744V     1.209V     1.884V
2.421ns   1.788V     1.617V     1.888V
3.371ns   1.798V     1.693V     1.89V
20ns      1.8V       1.71V      1.89V
[Falling Waveform]
R_fixture= 50.000
V_fixture= 1.800
V_fixture_min= 1.710
V_fixture_max= 1.890
|time   V(typ)   V(min)   V(max)
0s        1.8V       1.71V      1.89V
964ps     1.8V       1.71V      1.885V
1.253ns   1.814V     1.71V      1.58V
1.448ns   1.829V     1.71V      1.246V
1.775ns   1.802V     1.71V      937.6mV
2.748ns   1.331V     1.718V     706.4mV
4.184ns   1.023V     1.556V     688.6mV
5.365ns   986.7mV    1.345V     687.6mV
7.233ns   980.1mV    1.233V     687.7mV
20ns      979.8mV    1.209V     687.7mV
[Falling Waveform]
R_fixture= 50.000
V_fixture= 0.0
V_fixture_min= 0.0
V_fixture_max= 0.0
|time   V(typ)   V(min)   V(max)
0s        640.6mV    415.2mV    1.079V
654ps     640.6mV    415.2mV    1.073V
825ps     640.6mV    415.2mV    545.8mV
1.058ns   640.5mV    415.2mV    202.5mV
1.243ns   616.2mV    415.2mV    57.52mV
1.548ns   200.8mV    415.1mV    12.8mV
2.173ns   24.5mV     414.5mV    1.892mV
2.65ns    6.318mV    99.98mV    540.7uV
3.561ns   970.9uV    11.96mV    60.5uV
20ns      9.753nV    94.46nV    22.4nV
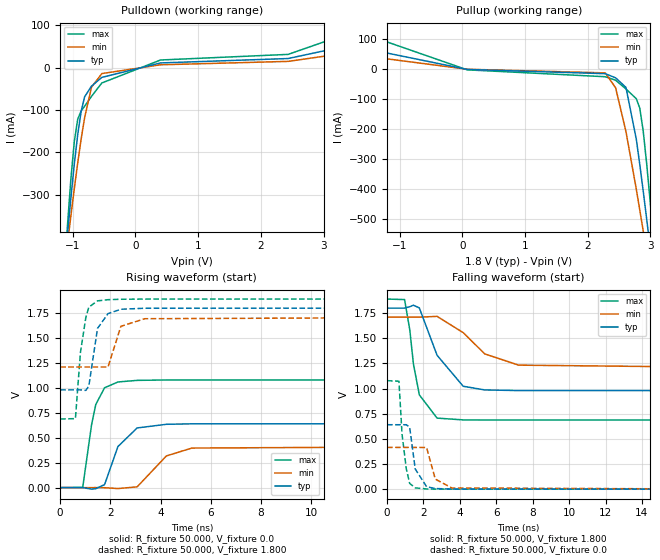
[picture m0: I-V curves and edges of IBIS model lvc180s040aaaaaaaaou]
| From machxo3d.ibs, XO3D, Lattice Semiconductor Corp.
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|   Model lvc180s040aaaaaaaaou
[Model] lvc180s040aaaaaaaaou
Model_type Output
Polarity   Non-Inverting
Enable   Active-High
Vmeas =  0.900V
Cref =  0.0F
Rref =  1.000M
Vref =  0.0V
C_comp   4.200pF   3.800pF   7.500pF
[Temperature Range]   25.000   0.105k   -40.000
[Voltage Range]   1.800V   1.710V   1.890V
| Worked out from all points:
|   slope of the pulldown table from 0 to 0.27 V, typ, clamps not added: 34 ohm
|   slope of the pullup table from 0 to 0.27 V, typ, clamps not added: 45.6 ohm
|   rising waveform, R_fixture 50.000, V_fixture 0.0: 20-80 % time 622ps typ, 949ps min, 414ps max; typ from 0 V to 0.641 V
|   rising waveform, R_fixture 50.000, V_fixture 1.800: 20-80 % time 363ps typ, 366ps min, 304ps max; typ from 0.98 V to 1.8 V
|   falling waveform, R_fixture 50.000, V_fixture 1.800: 20-80 % time 1.1ns typ, 1.77ns min, 622ps max; typ from 1.8 V to 0.98 V
|   falling waveform, R_fixture 50.000, V_fixture 0.0: 20-80 % time 386ps typ, 403ps min, 324ps max; typ from 0.641 V to 0 V
[Pulldown]
|Voltage   I(typ)   I(min)   I(max)
-1.8V     -1.678A    -1.372A    -2.208A
-1.085V   -396mA     -417.6mA   -375.7mA
-1.03V    -308.9mA   -350.6mA   -264.3mA
-975mV    -228.3mA   -286mA     -175.1mA
-920mV    -158.1mA   -224.8mA   -121.7mA
-865mV    -103.1mA   -168.3mA   -102.1mA
-810mV    -69.12mA   -118.3mA   -91.22mA
-700mV    -43.91mA   -46.17mA   -67.96mA
-535mV    -23.24mA   -14.27mA   -36.42mA
400mV     10.77mA    6.38mA     17.68mA
2.435V    21.14mA    14.41mA    30.89mA
3.6V      57.97mA    39.13mA    90.92mA
[Pullup]
|Voltage   I(typ)   I(min)   I(max)
-1.8V     78mA       49.41mA    132.8mA
80mV      -1.961mA   -1.338mA   -3.329mA
2.28V     -16.08mA   -13.43mA   -26.16mA
2.445V    -29.88mA   -63.06mA   -37.88mA
2.61V     -61.72mA   -208.6mA   -66.88mA
2.775V    -234mA     -399.9mA   -99.24mA
2.83V     -317.5mA   -468.5mA   -130.4mA
2.885V    -406.2mA   -538.5mA   -206.7mA
2.94V     -498.2mA   -609.7mA   -315mA
2.995V    -592.6mA   -681.8mA   -438.3mA
3.05V     -688.8mA   -754.7mA   -569.3mA
3.6V      -1.692A    -1.506A    -1.994A
[Ramp]
| variable   typ   min   max
dV/dt_r   0.384/0.627n   0.249/0.943n   0.647/0.409n
dV/dt_f   0.492/1.088n   0.301/1.765n   0.721/0.622n
R_load = 50.000
[Rising Waveform]
R_fixture= 50.000
V_fixture= 0.0
V_fixture_min= 0.0
V_fixture_max= 0.0
|time   V(typ)   V(min)   V(max)
0s        4.812nV    48.48nV    2.958nV
899ps     115.7uV    2.148uV    2.376mV
1.252ns   -15.47mV   117uV      630.1mV
1.419ns   -10.69mV   296.3uV    833.3mV
1.77ns    30.08mV    -898.4uV   1.001V
2.303ns   411.9mV    -9.352mV   1.059V
3.067ns   598.2mV    7.636mV    1.075V
4.234ns   634.8mV    317.7mV    1.079V
5.248ns   639.4mV    396.6mV    1.079V
20ns      640.6mV    415.2mV    1.079V
[Rising Waveform]
R_fixture= 50.000
V_fixture= 1.800
V_fixture_min= 1.710
V_fixture_max= 1.890
|time   V(typ)   V(min)   V(max)
0s        979.8mV    1.209V     687.7mV
608ps     979.8mV    1.209V     691.8mV
809ps     979.8mV    1.209V     1.356V
1.024ns   974.3mV    1.209V     1.707V
1.143ns   1.018V     1.209V     1.809V
1.489ns   1.596V     1.209V     1.872V
1.907ns   1.744V     1.209V     1.884V
2.421ns   1.788V     1.617V     1.888V
3.371ns   1.798V     1.693V     1.89V
20ns      1.8V       1.71V      1.89V
[Falling Waveform]
R_fixture= 50.000
V_fixture= 1.800
V_fixture_min= 1.710
V_fixture_max= 1.890
|time   V(typ)   V(min)   V(max)
0s        1.8V       1.71V      1.89V
964ps     1.8V       1.71V      1.885V
1.253ns   1.814V     1.71V      1.58V
1.448ns   1.829V     1.71V      1.246V
1.775ns   1.802V     1.71V      937.6mV
2.748ns   1.331V     1.718V     706.4mV
4.184ns   1.023V     1.556V     688.6mV
5.365ns   986.7mV    1.345V     687.6mV
7.233ns   980.1mV    1.233V     687.7mV
20ns      979.8mV    1.209V     687.7mV
[Falling Waveform]
R_fixture= 50.000
V_fixture= 0.0
V_fixture_min= 0.0
V_fixture_max= 0.0
|time   V(typ)   V(min)   V(max)
0s        640.6mV    415.2mV    1.079V
654ps     640.6mV    415.2mV    1.073V
825ps     640.6mV    415.2mV    545.8mV
1.058ns   640.5mV    415.2mV    202.5mV
1.243ns   616.2mV    415.2mV    57.52mV
1.548ns   200.8mV    415.1mV    12.8mV
2.173ns   24.5mV     414.5mV    1.892mV
2.65ns    6.318mV    99.98mV    540.7uV
3.561ns   970.9uV    11.96mV    60.5uV
20ns      9.753nV    94.46nV    22.4nV
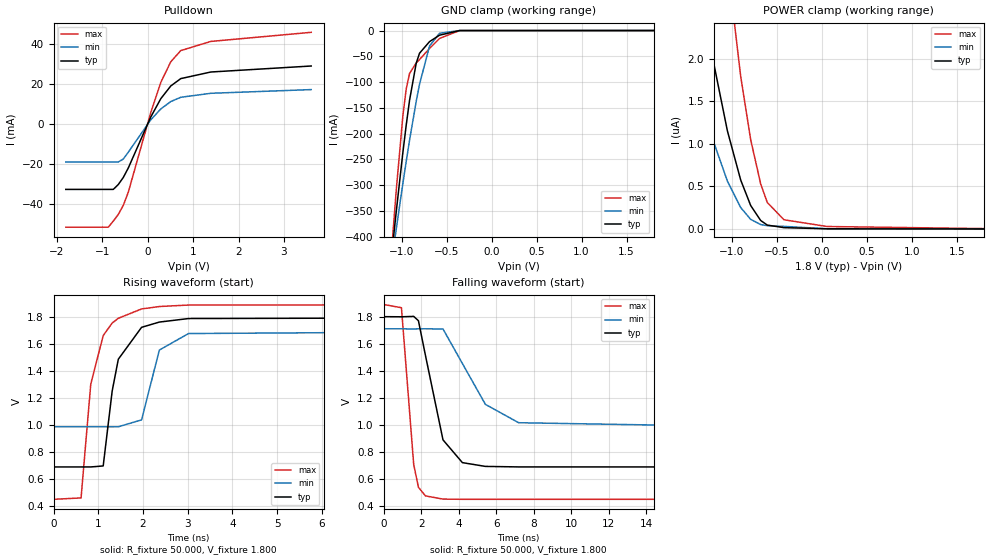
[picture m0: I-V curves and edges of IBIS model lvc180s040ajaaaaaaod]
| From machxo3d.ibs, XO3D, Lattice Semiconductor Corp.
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|   Model lvc180s040ajaaaaaaod
[Model] lvc180s040ajaaaaaaod
Model_type I/O_open_drain
Polarity   Non-Inverting
Enable   Active-Low
Vinl =  0.630V
Vinh =  1.170V
Vmeas =  0.900V
Cref =  0.0F
Rref = 10.00k
Vref = 1.80V
C_comp   4.200pF   3.800pF   7.500pF
[Temperature Range]   25.000   0.105k   -40.000
[Voltage Range]   1.800V   1.710V   1.890V
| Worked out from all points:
|   slope of the pulldown table from 0 to 0.27 V, typ, clamps not added: 22.7 ohm
|   GND clamp passes 1 mA (typ) near -0.44 V on its own axis
|   rising waveform, R_fixture 50.000, V_fixture 1.800: 20-80 % time 347ps typ, 359ps min, 348ps max; typ from 0.688 V to 1.8 V
|   falling waveform, R_fixture 50.000, V_fixture 1.800: 20-80 % time 960ps typ, 1.72ns min, 459ps max; typ from 1.8 V to 0.688 V
[Pulldown]
|Voltage   I(typ)   I(min)   I(max)
-1.8V     -32.67mA   -18.98mA   -51.52mA
-865mV    -32.67mA   -18.98mA   -51.52mA
-755mV    -32.67mA   -18.98mA   -48.5mA
-645mV    -30.22mA   -18.98mA   -45.17mA
-535mV    -26.71mA   -17.49mA   -40.65mA
-425mV    -21.97mA   -14.07mA   -34.06mA
70mV      3.511mA    2.096mA    5.77mA
290mV     12.64mA    7.511mA    20.77mA
510mV     19mA       11.21mA    31.08mA
730mV     22.67mA    13.34mA    36.66mA
1.39V     25.96mA    15.33mA    41.23mA
3.6V      28.96mA    17.18mA    45.78mA
[GND_clamp]
|Voltage   I(typ)   I(min)   I(max)
-1.8V     -1.677A    -1.372A    -2.207A
-1.097V   -411.6mA   -430.5mA   -392.9mA
-1.06V    -351mA     -384.7mA   -309.8mA
-986mV    -235.9mA   -295.9mA   -164.7mA
-949mV    -183mA     -253.4mA   -113mA
-912mV    -135mA     -212.5mA   -83.33mA
-838mV    -63.16mA   -137.2mA   -62.66mA
-801mV    -43.93mA   -103.8mA   -56.25mA
-690mV    -21.49mA   -30.06mA   -34.72mA
-579mV    -9.043mA   -5.343mA   -15.31mA
-357mV    -110.3uA   -52.32uA   -166.6uA
1.8V      0A         0A         0A
[POWER_clamp]
|Voltage   I(typ)   I(min)   I(max)
-1.8V     6.918uA    4.075uA    15.53uA
-1.641V   5.335uA    3.081uA    12.17uA
-1.382V   3.16uA     1.741uA    7.507uA
-1.197V   1.931uA    1.01uA     4.843uA
-1.049V   1.156uA    564.3nA    3.128uA
-901mV    576.3nA    251.8nA    1.796uA
-790mV    276.2nA    113.2nA    1.051uA
-679mV    99.59nA    51.81nA    530.4nA
-605mV    45.39nA    37.93nA    310.9nA
-420mV    15.42nA    30.13nA    108.2nA
61mV      1.594nA    2.49nA     28.82nA
1.8V      0A         0A         4.229nA
[Ramp]
| variable   typ   min   max
dV/dt_r   0.667/0.343n   0.435/0.356n   0.865/0.347n
dV/dt_f   0.667/0.962n   0.435/1.705n   0.865/0.459n
R_load = 50.000
[Rising Waveform]
R_fixture= 50.000
V_fixture= 1.800
V_fixture_min= 1.710
V_fixture_max= 1.890
|time   V(typ)   V(min)   V(max)
0s        687.7mV    984.9mV    448.1mV
616ps     687.7mV    984.9mV    458.6mV
833ps     687.8mV    984.9mV    1.301V
1.111ns   695.2mV    984.8mV    1.66V
1.312ns   1.25V      984.5mV    1.753V
1.449ns   1.485V     985.1mV    1.788V
1.969ns   1.721V     1.036V     1.857V
2.367ns   1.76V      1.553V     1.875V
3.019ns   1.786V     1.675V     1.886V
20ns      1.8V       1.71V      1.89V
[Falling Waveform]
R_fixture= 50.000
V_fixture= 1.800
V_fixture_min= 1.710
V_fixture_max= 1.890
|time   V(typ)   V(min)   V(max)
0s        1.8V       1.71V      1.89V
948ps     1.799V     1.71V      1.866V
1.601ns   1.802V     1.709V     705.6mV
1.853ns   1.77V      1.71V      537.3mV
2.227ns   1.513V     1.71V      473.6mV
3.161ns   888.1mV    1.709V     449.8mV
4.195ns   719.6mV    1.453V     448.1mV
5.42ns    691.7mV    1.151V     448.1mV
7.191ns   687.9mV    1.015V     448.1mV
20ns      687.6mV    984.8mV    448mV
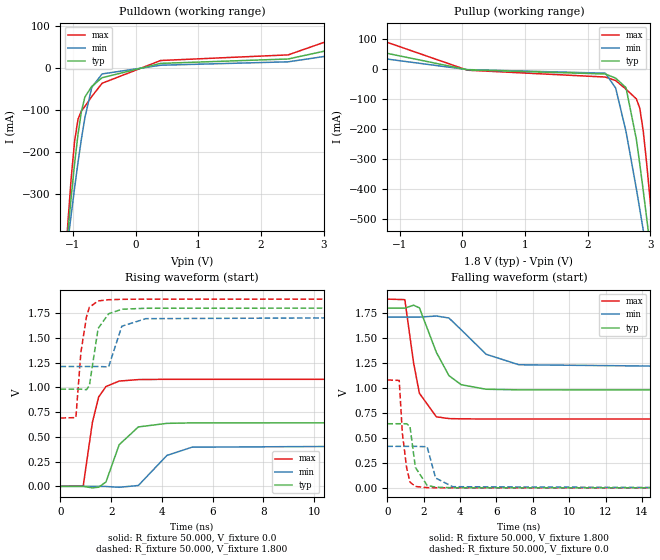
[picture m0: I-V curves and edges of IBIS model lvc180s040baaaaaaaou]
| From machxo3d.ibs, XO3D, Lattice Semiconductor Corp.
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|   Model lvc180s040baaaaaaaou
[Model] lvc180s040baaaaaaaou
Model_type Output
Polarity   Non-Inverting
Enable   Active-High
Vmeas =  0.900V
Cref =  0.0F
Rref =  1.000M
Vref =  0.0V
C_comp   4.200pF   3.800pF   7.500pF
[Temperature Range]   25.000   0.105k   -40.000
[Voltage Range]   1.800V   1.710V   1.890V
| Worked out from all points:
|   slope of the pulldown table from 0 to 0.27 V, typ, clamps not added: 34 ohm
|   slope of the pullup table from 0 to 0.27 V, typ, clamps not added: 45.5 ohm
|   rising waveform, R_fixture 50.000, V_fixture 0.0: 20-80 % time 628ps typ, 951ps min, 411ps max; typ from 0.001 V to 0.642 V
|   rising waveform, R_fixture 50.000, V_fixture 1.800: 20-80 % time 362ps typ, 366ps min, 303ps max; typ from 0.981 V to 1.8 V
|   falling waveform, R_fixture 50.000, V_fixture 1.800: 20-80 % time 1.1ns typ, 1.76ns min, 625ps max; typ from 1.8 V to 0.981 V
|   falling waveform, R_fixture 50.000, V_fixture 0.0: 20-80 % time 386ps typ, 404ps min, 327ps max; typ from 0.642 V to 0.001 V
[Pulldown]
|Voltage   I(typ)   I(min)   I(max)
-1.8V     -1.678A    -1.372A    -2.208A
-1.085V   -396mA     -417.6mA   -375.7mA
-1.03V    -309mA     -350.6mA   -264.3mA
-975mV    -228.3mA   -286mA     -175.1mA
-920mV    -158.1mA   -224.8mA   -121.7mA
-865mV    -103.2mA   -168.3mA   -102.1mA
-810mV    -69.13mA   -118.3mA   -91.25mA
-700mV    -43.93mA   -46.18mA   -67.99mA
-535mV    -23.26mA   -14.28mA   -36.46mA
400mV     10.74mA    6.36mA     17.6mA
2.435V    21.19mA    14.46mA    30.93mA
3.6V      58.65mA    40.11mA    91.46mA
[Pullup]
|Voltage   I(typ)   I(min)   I(max)
-1.8V     78.72mA    50.31mA    133.4mA
80mV      -1.967mA   -1.342mA   -3.339mA
2.28V     -16.11mA   -13.44mA   -26.22mA
2.445V    -29.9mA    -63.07mA   -37.92mA
2.61V     -61.73mA   -208.6mA   -66.9mA
2.775V    -234mA     -399.9mA   -99.26mA
2.83V     -317.5mA   -468.5mA   -130.4mA
2.885V    -406.2mA   -538.5mA   -206.7mA
2.94V     -498.2mA   -609.7mA   -315.1mA
2.995V    -592.7mA   -681.9mA   -438.4mA
3.05V     -688.8mA   -754.7mA   -569.3mA
3.6V      -1.692A    -1.506A    -1.995A
[Ramp]
| variable   typ   min   max
dV/dt_r   0.385/0.631n   0.249/0.940n   0.648/0.409n
dV/dt_f   0.491/1.089n   0.300/1.762n   0.720/0.623n
R_load = 50.000
[Rising Waveform]
R_fixture= 50.000
V_fixture= 0.0
V_fixture_min= 0.0
V_fixture_max= 0.0
|time   V(typ)   V(min)   V(max)
0s        714.8uV    493.6uV    1.055mV
899ps     706.8uV    520.4uV    5.309mV
1.26ns    -14.58mV   610.1uV    646.2mV
1.509ns   -7.692mV   672.9uV    902.9mV
1.796ns   45.2mV     -677.6uV   1.008V
2.316ns   420.7mV    -8.747mV   1.063V
3.072ns   600.2mV    9.105mV    1.078V
4.2ns     636.3mV    312.9mV    1.081V
5.189ns   641.1mV    395.8mV    1.081V
20ns      642.4mV    416.2mV    1.081V
[Rising Waveform]
R_fixture= 50.000
V_fixture= 1.800
V_fixture_min= 1.710
V_fixture_max= 1.890
|time   V(typ)   V(min)   V(max)
0s        981.3mV    1.21V      690.2mV
608ps     981.3mV    1.21V      694.3mV
807ps     981.3mV    1.21V      1.354V
1.024ns   975.8mV    1.21V      1.708V
1.141ns   1.017V     1.21V      1.808V
1.486ns   1.594V     1.21V      1.872V
1.898ns   1.742V     1.206V     1.884V
2.422ns   1.788V     1.617V     1.888V
3.369ns   1.798V     1.693V     1.89V
20ns      1.8V       1.71V      1.89V
[Falling Waveform]
R_fixture= 50.000
V_fixture= 1.800
V_fixture_min= 1.710
V_fixture_max= 1.890
|time   V(typ)   V(min)   V(max)
0s        1.8V       1.71V      1.89V
963ps     1.8V       1.71V      1.885V
1.445ns   1.829V     1.71V      1.251V
1.765ns   1.803V     1.71V      947.3mV
2.695ns   1.358V     1.721V     711.9mV
3.388ns   1.124V     1.701V     694.2mV
4.065ns   1.033V     1.583V     691.2mV
5.433ns   987.7mV    1.338V     690.2mV
7.235ns   981.7mV    1.233V     690.2mV
20ns      981.3mV    1.21V      690.2mV
[Falling Waveform]
R_fixture= 50.000
V_fixture= 0.0
V_fixture_min= 0.0
V_fixture_max= 0.0
|time   V(typ)   V(min)   V(max)
0s        642.4mV    416.2mV    1.081V
654ps     642.5mV    416.2mV    1.076V
823ps     642.4mV    416.2mV    553.8mV
1.058ns   642.4mV    416.2mV    206.1mV
1.245ns   615.9mV    416.2mV    58.8mV
1.544ns   205.5mV    416mV      14.32mV
2.187ns   25.49mV    412.1mV    2.881mV
2.656ns   7.175mV    99.06mV    1.563mV
3.597ns   1.75mV     12.08mV    1.107mV
20ns      714.8uV    493.6uV    1.055mV
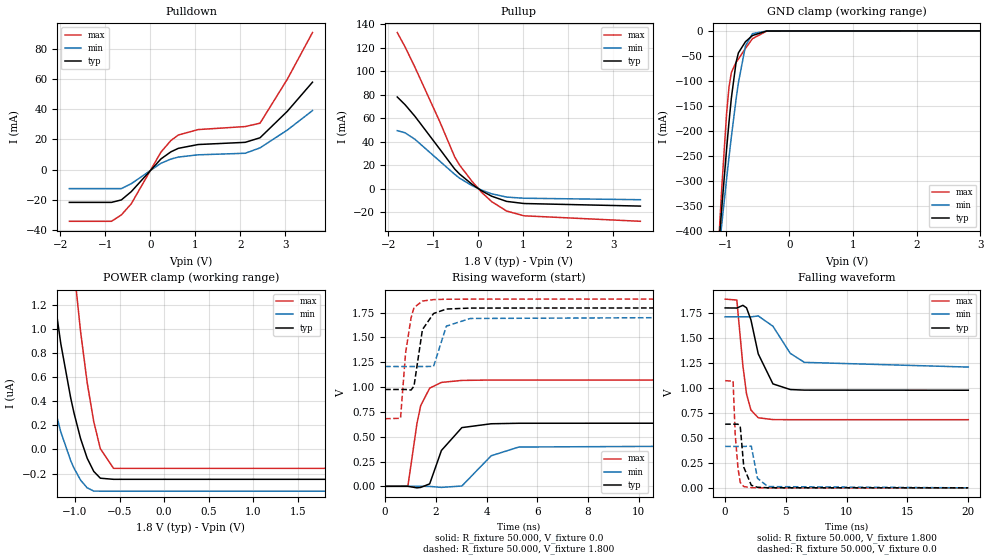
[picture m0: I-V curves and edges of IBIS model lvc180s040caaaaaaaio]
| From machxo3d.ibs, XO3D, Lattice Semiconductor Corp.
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|   Model lvc180s040caaaaaaaio
[Model] lvc180s040caaaaaaaio
Model_type I/O
Polarity   Non-Inverting
Enable   Active-Low
Vinl =  0.630V
Vinh =  1.170V
Vmeas =  0.900V
Cref =  0.0F
Rref =  1.000M
Vref =  0.0V
C_comp   4.200pF   3.800pF   7.500pF
[Temperature Range]   25.000   0.105k   -40.000
[Voltage Range]   1.800V   1.710V   1.890V
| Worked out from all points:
|   slope of the pulldown table from 0 to 0.27 V, typ, clamps not added: 34 ohm
|   slope of the pullup table from 0 to 0.27 V, typ, clamps not added: 45.6 ohm
|   GND clamp passes 1 mA (typ) near -0.44 V on its own axis
|   rising waveform, R_fixture 50.000, V_fixture 0.0: 20-80 % time 620ps typ, 954ps min, 412ps max; typ from 0 V to 0.636 V
|   rising waveform, R_fixture 50.000, V_fixture 1.800: 20-80 % time 365ps typ, 367ps min, 307ps max; typ from 0.976 V to 1.8 V
|   falling waveform, R_fixture 50.000, V_fixture 1.800: 20-80 % time 1.1ns typ, 1.78ns min, 619ps max; typ from 1.8 V to 0.976 V
|   falling waveform, R_fixture 50.000, V_fixture 0.0: 20-80 % time 376ps typ, 402ps min, 321ps max; typ from 0.636 V to 0 V
[Pulldown]
|Voltage   I(typ)   I(min)   I(max)
-1.8V     -21.78mA   -12.65mA   -34.34mA
-865mV    -21.78mA   -12.65mA   -34.34mA
-645mV    -20.15mA   -12.65mA   -30.11mA
-425mV    -14.65mA   -9.378mA   -22.7mA
235mV     7.083mA    4.214mA    11.64mA
455mV     11.78mA    6.962mA    19.3mA
620mV     14.1mA     8.304mA    22.95mA
1.06V     16.63mA    9.799mA    26.56mA
2.105V    18.09mA    10.83mA    28.56mA
2.435V    21.12mA    14.41mA    30.8mA
3.04V     38.66mA    26.22mA    59.96mA
3.6V      58.02mA    39.17mA    90.97mA
[Pullup]
|Voltage   I(typ)   I(min)   I(max)
-1.8V     78.06mA    49.44mA    132.9mA
-1.625V   71.44mA    47.57mA    120.6mA
-1.405V   61.52mA    41.99mA    103.2mA
-855mV    33.68mA    23.41mA    57mA
-525mV    16.78mA    12.26mA    27.13mA
-415mV    12.44mA    8.948mA    20.06mA
-140mV    3.787mA    2.633mA    6.305mA
80mV      -1.961mA   -1.338mA   -3.329mA
300mV     -6.456mA   -4.362mA   -11.09mA
630mV     -10.81mA   -7.147mA   -19.03mA
1.015V    -12.62mA   -8.118mA   -23.07mA
3.6V      -14.81mA   -9.369mA   -27.75mA
[GND_clamp]
|Voltage   I(typ)   I(min)   I(max)
-1.8V     -1.677A    -1.372A    -2.207A
-1.097V   -411.7mA   -430.5mA   -393mA
-1.06V    -351mA     -384.7mA   -309.9mA
-986mV    -235.9mA   -295.9mA   -164.8mA
-949mV    -183mA     -253.4mA   -113.1mA
-912mV    -135mA     -212.5mA   -83.39mA
-838mV    -63.2mA    -137.2mA   -62.73mA
-801mV    -43.97mA   -103.8mA   -56.32mA
-690mV    -21.54mA   -30.09mA   -34.79mA
-579mV    -9.102mA   -5.388mA   -15.4mA
-357mV    -191.3uA   -96.81uA   -298.1uA
3.6V      109.7uA    43.11uA    257.2uA
[POWER_clamp]
|Voltage   I(typ)   I(min)   I(max)
-1.8V     5.719uA    2.929uA    14.07uA
-1.567V   3.495uA    1.63uA     8.906uA
-1.308V   1.654uA    574.5nA    4.658uA
-1.16V    879.1nA    145.5nA    2.867uA
-1.049V   428.7nA    -92.09nA   1.807uA
-1.012V   303.4nA    -154.9nA   1.506uA
-938mV    90.13nA    -254.7nA   980.1nA
-864mV    -72.36nA   -318.6nA   555.1nA
-790mV    -182.4nA   -345.7nA   230.3nA
-716mV    -238.9nA   -346.3nA   5.99nA
-568mV    -248.1nA   -346.3nA   -157.2nA
1.8V      -248.1nA   -346.3nA   -157.2nA
[Ramp]
| variable   typ   min   max
dV/dt_r   0.382/0.630n   0.248/0.933n   0.643/0.410n
dV/dt_f   0.493/1.096n   0.301/1.778n   0.723/0.620n
R_load = 50.000
[Rising Waveform]
R_fixture= 50.000
V_fixture= 0.0
V_fixture_min= 0.0
V_fixture_max= 0.0
|time   V(typ)   V(min)   V(max)
0s        4.637nV    47.96nV    2.735nV
899ps     113uV      2.085uV    2.593mV
1.257ns   -15.53mV   116.9uV    634.6mV
1.403ns   -10.99mV   295uV      813mV
1.758ns   24.88mV    -921.6uV   989.3mV
2.221ns   361.5mV    -10.81mV   1.047V
3.026ns   591.5mV    3.183mV    1.067V
4.181ns   630.3mV    307.7mV    1.071V
5.271ns   635.3mV    395.9mV    1.071V
20ns      636.4mV    413.8mV    1.071V
[Rising Waveform]
R_fixture= 50.000
V_fixture= 1.800
V_fixture_min= 1.710
V_fixture_max= 1.890
|time   V(typ)   V(min)   V(max)
0s        975.6mV    1.207V     681.2mV
608ps     975.6mV    1.207V     685.2mV
807ps     975.6mV    1.207V     1.342V
1.024ns   970.1mV    1.207V     1.698V
1.139ns   1.009V     1.207V     1.801V
1.472ns   1.579V     1.207V     1.867V
1.91ns    1.741V     1.208V     1.881V
2.415ns   1.786V     1.614V     1.885V
3.352ns   1.796V     1.691V     1.886V
20ns      1.798V     1.709V     1.886V
[Falling Waveform]
R_fixture= 50.000
V_fixture= 1.800
V_fixture_min= 1.710
V_fixture_max= 1.890
|time   V(typ)   V(min)   V(max)
0s        1.798V     1.709V     1.886V
961ps     1.797V     1.709V     1.877V
1.461ns   1.824V     1.709V     1.219V
1.758ns   1.799V     1.709V     939mV
2.121ns   1.679V     1.709V     777.6mV
2.722ns   1.339V     1.718V     700.5mV
3.931ns   1.039V     1.615V     682.2mV
5.358ns   982.6mV    1.344V     681.2mV
6.52ns    976.8mV    1.254V     681.2mV
20ns      975.6mV    1.207V     681.1mV
[Falling Waveform]
R_fixture= 50.000
V_fixture= 0.0
V_fixture_min= 0.0
V_fixture_max= 0.0
|time   V(typ)   V(min)   V(max)
0s        636.4mV    413.8mV    1.071V
653ps     636.4mV    413.8mV    1.066V
825ps     636.4mV    413.8mV    536.3mV
1.055ns   636.5mV    413.8mV    198mV
1.243ns   612mV      413.8mV    54.24mV
1.536ns   205.7mV    413.7mV    12.96mV
2.151ns   25.89mV    416.6mV    1.992mV
2.662ns   6.001mV    95.19mV    442uV
3.514ns   1.047mV    12.85mV    74.41uV
20ns      2.005nV    93.37nV    12.24nV
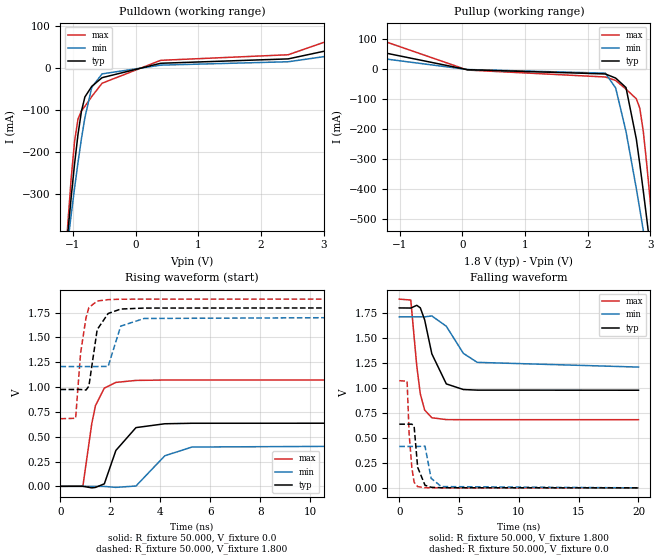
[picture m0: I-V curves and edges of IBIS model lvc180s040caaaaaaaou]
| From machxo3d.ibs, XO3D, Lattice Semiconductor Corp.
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|   Model lvc180s040caaaaaaaou
[Model] lvc180s040caaaaaaaou
Model_type Output
Polarity   Non-Inverting
Enable   Active-High
Vmeas =  0.900V
Cref =  0.0F
Rref =  1.000M
Vref =  0.0V
C_comp   4.200pF   3.800pF   7.500pF
[Temperature Range]   25.000   0.105k   -40.000
[Voltage Range]   1.800V   1.710V   1.890V
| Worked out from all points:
|   slope of the pulldown table from 0 to 0.27 V, typ, clamps not added: 33.8 ohm
|   slope of the pullup table from 0 to 0.27 V, typ, clamps not added: 45.6 ohm
|   rising waveform, R_fixture 50.000, V_fixture 0.0: 20-80 % time 620ps typ, 954ps min, 412ps max; typ from 0 V to 0.636 V
|   rising waveform, R_fixture 50.000, V_fixture 1.800: 20-80 % time 365ps typ, 367ps min, 307ps max; typ from 0.976 V to 1.8 V
|   falling waveform, R_fixture 50.000, V_fixture 1.800: 20-80 % time 1.1ns typ, 1.78ns min, 619ps max; typ from 1.8 V to 0.976 V
|   falling waveform, R_fixture 50.000, V_fixture 0.0: 20-80 % time 376ps typ, 402ps min, 321ps max; typ from 0.636 V to 0 V
[Pulldown]
|Voltage   I(typ)   I(min)   I(max)
-1.8V     -1.678A    -1.372A    -2.208A
-1.085V   -396mA     -417.6mA   -375.8mA
-1.03V    -309mA     -350.6mA   -264.4mA
-975mV    -228.4mA   -286mA     -175.1mA
-920mV    -158.2mA   -224.8mA   -121.7mA
-865mV    -103.2mA   -168.3mA   -102.1mA
-810mV    -69.16mA   -118.3mA   -91.29mA
-700mV    -43.96mA   -46.2mA    -68.03mA
-535mV    -23.3mA    -14.32mA   -36.51mA
400mV     10.84mA    6.409mA    17.83mA
2.435V    21.22mA    14.45mA    31.04mA
3.6V      58.13mA    39.21mA    91.24mA
[Pullup]
|Voltage   I(typ)   I(min)   I(max)
-1.8V     78.17mA    49.49mA    133.1mA
80mV      -1.86mA    -1.301mA   -3.087mA
2.28V     -16.16mA   -13.47mA   -26.29mA
2.445V    -29.93mA   -63.08mA   -37.97mA
2.61V     -61.75mA   -208.6mA   -66.94mA
2.775V    -234.1mA   -399.9mA   -99.28mA
2.83V     -317.5mA   -468.5mA   -130.4mA
2.885V    -406.2mA   -538.5mA   -206.8mA
2.94V     -498.3mA   -609.7mA   -315.1mA
2.995V    -592.7mA   -681.9mA   -438.4mA
3.05V     -688.8mA   -754.7mA   -569.4mA
3.6V      -1.692A    -1.506A    -1.995A
[Ramp]
| variable   typ   min   max
dV/dt_r   0.382/0.630n   0.248/0.933n   0.643/0.410n
dV/dt_f   0.493/1.096n   0.301/1.778n   0.723/0.620n
R_load = 50.000
[Rising Waveform]
R_fixture= 50.000
V_fixture= 0.0
V_fixture_min= 0.0
V_fixture_max= 0.0
|time   V(typ)   V(min)   V(max)
0s        4.637nV    47.96nV    2.735nV
899ps     113uV      2.085uV    2.593mV
1.257ns   -15.53mV   116.9uV    634.6mV
1.403ns   -10.99mV   295uV      813mV
1.758ns   24.88mV    -921.6uV   989.3mV
2.221ns   361.5mV    -10.81mV   1.047V
3.026ns   591.5mV    3.183mV    1.067V
4.181ns   630.3mV    307.7mV    1.071V
5.271ns   635.3mV    395.9mV    1.071V
20ns      636.4mV    413.8mV    1.071V
[Rising Waveform]
R_fixture= 50.000
V_fixture= 1.800
V_fixture_min= 1.710
V_fixture_max= 1.890
|time   V(typ)   V(min)   V(max)
0s        975.6mV    1.207V     681.2mV
608ps     975.6mV    1.207V     685.2mV
807ps     975.6mV    1.207V     1.342V
1.024ns   970.1mV    1.207V     1.698V
1.139ns   1.009V     1.207V     1.801V
1.472ns   1.579V     1.207V     1.867V
1.91ns    1.741V     1.208V     1.881V
2.415ns   1.786V     1.614V     1.885V
3.352ns   1.796V     1.691V     1.886V
20ns      1.798V     1.709V     1.886V
[Falling Waveform]
R_fixture= 50.000
V_fixture= 1.800
V_fixture_min= 1.710
V_fixture_max= 1.890
|time   V(typ)   V(min)   V(max)
0s        1.798V     1.709V     1.886V
961ps     1.797V     1.709V     1.877V
1.461ns   1.824V     1.709V     1.219V
1.758ns   1.799V     1.709V     939mV
2.121ns   1.679V     1.709V     777.6mV
2.722ns   1.339V     1.718V     700.5mV
3.931ns   1.039V     1.615V     682.2mV
5.358ns   982.6mV    1.344V     681.2mV
6.52ns    976.8mV    1.254V     681.2mV
20ns      975.6mV    1.207V     681.1mV
[Falling Waveform]
R_fixture= 50.000
V_fixture= 0.0
V_fixture_min= 0.0
V_fixture_max= 0.0
|time   V(typ)   V(min)   V(max)
0s        636.4mV    413.8mV    1.071V
653ps     636.4mV    413.8mV    1.066V
825ps     636.4mV    413.8mV    536.3mV
1.055ns   636.5mV    413.8mV    198mV
1.243ns   612mV      413.8mV    54.24mV
1.536ns   205.7mV    413.7mV    12.96mV
2.151ns   25.89mV    416.6mV    1.992mV
2.662ns   6.001mV    95.19mV    442uV
3.514ns   1.047mV    12.85mV    74.41uV
20ns      2.005nV    93.37nV    12.24nV
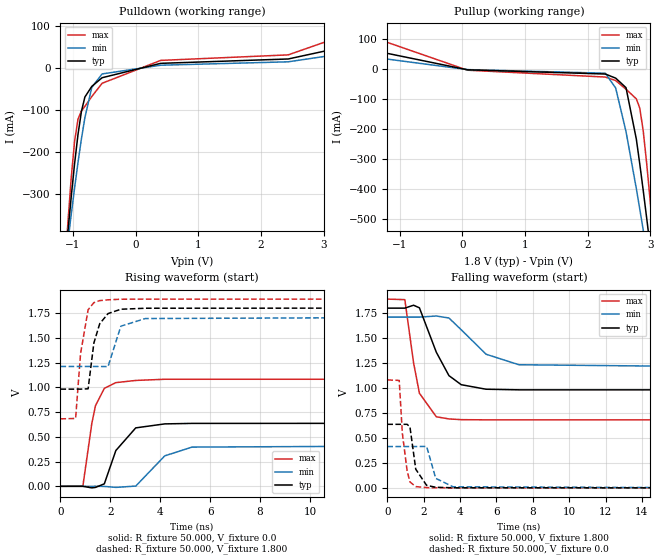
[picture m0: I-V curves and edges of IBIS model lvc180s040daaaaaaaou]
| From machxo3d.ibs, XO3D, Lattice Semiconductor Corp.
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|   Model lvc180s040daaaaaaaou
[Model] lvc180s040daaaaaaaou
Model_type Output
Polarity   Non-Inverting
Enable   Active-High
Vmeas =  0.900V
Cref =  0.0F
Rref =  1.000M
Vref =  0.0V
C_comp   4.200pF   3.800pF   7.500pF
[Temperature Range]   25.000   0.105k   -40.000
[Voltage Range]   1.800V   1.710V   1.890V
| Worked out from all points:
|   slope of the pulldown table from 0 to 0.27 V, typ, clamps not added: 33.8 ohm
|   slope of the pullup table from 0 to 0.27 V, typ, clamps not added: 45.5 ohm
|   rising waveform, R_fixture 50.000, V_fixture 0.0: 20-80 % time 620ps typ, 965ps min, 424ps max; typ from 0 V to 0.636 V
|   rising waveform, R_fixture 50.000, V_fixture 1.800: 20-80 % time 361ps typ, 367ps min, 309ps max; typ from 0.981 V to 1.8 V
|   falling waveform, R_fixture 50.000, V_fixture 1.800: 20-80 % time 1.1ns typ, 1.77ns min, 632ps max; typ from 1.8 V to 0.981 V
|   falling waveform, R_fixture 50.000, V_fixture 0.0: 20-80 % time 376ps typ, 402ps min, 328ps max; typ from 0.636 V to 0 V
[Pulldown]
|Voltage   I(typ)   I(min)   I(max)
-1.8V     -1.678A    -1.372A    -2.208A
-1.085V   -396mA     -417.6mA   -375.8mA
-1.03V    -309mA     -350.6mA   -264.4mA
-975mV    -228.4mA   -286mA     -175.1mA
-920mV    -158.2mA   -224.8mA   -121.7mA
-865mV    -103.2mA   -168.3mA   -102.1mA
-810mV    -69.16mA   -118.3mA   -91.29mA
-700mV    -43.96mA   -46.2mA    -68.03mA
-535mV    -23.3mA    -14.32mA   -36.51mA
400mV     10.84mA    6.409mA    17.83mA
2.435V    21.19mA    14.46mA    30.93mA
3.6V      58.65mA    40.11mA    91.46mA
[Pullup]
|Voltage   I(typ)   I(min)   I(max)
-1.8V     78.72mA    50.31mA    133.4mA
80mV      -1.967mA   -1.342mA   -3.339mA
2.28V     -16.16mA   -13.47mA   -26.29mA
2.445V    -29.93mA   -63.08mA   -37.97mA
2.61V     -61.75mA   -208.6mA   -66.94mA
2.775V    -234.1mA   -399.9mA   -99.28mA
2.83V     -317.5mA   -468.5mA   -130.4mA
2.885V    -406.2mA   -538.5mA   -206.8mA
2.94V     -498.3mA   -609.7mA   -315.1mA
2.995V    -592.7mA   -681.9mA   -438.4mA
3.05V     -688.8mA   -754.7mA   -569.4mA
3.6V      -1.692A    -1.506A    -1.995A
[Ramp]
| variable   typ   min   max
dV/dt_r   0.382/0.630n   0.248/0.933n   0.649/0.420n
dV/dt_f   0.491/1.089n   0.300/1.762n   0.725/0.634n
R_load = 50.000
[Rising Waveform]
R_fixture= 50.000
V_fixture= 0.0
V_fixture_min= 0.0
V_fixture_max= 0.0
|time   V(typ)   V(min)   V(max)
0s        4.637nV    47.96nV    2.735nV
899ps     113uV      2.075uV    2.593mV
1.257ns   -15.53mV   116.9uV    634.6mV
1.403ns   -10.99mV   295uV      813mV
1.758ns   24.88mV    -898uV     989.3mV
2.221ns   361.5mV    -10.83mV   1.047V
3.018ns   590.1mV    2.472mV    1.069V
4.181ns   630.3mV    307.7mV    1.081V
5.273ns   635.3mV    396mV      1.081V
20ns      636.4mV    413.8mV    1.081V
[Rising Waveform]
R_fixture= 50.000
V_fixture= 1.800
V_fixture_min= 1.710
V_fixture_max= 1.890
|time   V(typ)   V(min)   V(max)
0s        981.3mV    1.21V      681.2mV
608ps     981.3mV    1.21V      685.2mV
807ps     981.3mV    1.21V      1.342V
1.109ns   984.7mV    1.21V      1.783V
1.34ns    1.447V     1.21V      1.855V
1.573ns   1.641V     1.21V      1.875V
1.907ns   1.744V     1.209V     1.883V
2.422ns   1.788V     1.617V     1.889V
3.403ns   1.798V     1.694V     1.89V
20ns      1.8V       1.71V      1.89V
[Falling Waveform]
R_fixture= 50.000
V_fixture= 1.800
V_fixture_min= 1.710
V_fixture_max= 1.890
|time   V(typ)   V(min)   V(max)
0s        1.8V       1.71V      1.89V
963ps     1.8V       1.71V      1.885V
1.445ns   1.829V     1.71V      1.251V
1.765ns   1.803V     1.71V      947.3mV
2.695ns   1.358V     1.721V     711.9mV
3.388ns   1.124V     1.701V     690.3mV
4.065ns   1.033V     1.583V     683mV
5.433ns   987.7mV    1.338V     681.2mV
7.235ns   981.7mV    1.233V     681.1mV
20ns      981.3mV    1.21V      681.2mV
[Falling Waveform]
R_fixture= 50.000
V_fixture= 0.0
V_fixture_min= 0.0
V_fixture_max= 0.0
|time   V(typ)   V(min)   V(max)
0s        636.4mV    413.8mV    1.081V
654ps     636.4mV    413.8mV    1.076V
825ps     636.4mV    413.8mV    549.3mV
1.088ns   636.4mV    413.8mV    171mV
1.245ns   609.9mV    413.8mV    58.8mV
1.564ns   186.5mV    413.7mV    12.85mV
2.161ns   24.86mV    415.2mV    2.264mV
2.662ns   6.001mV    95.19mV    576.5uV
3.616ns   842.8uV    10.62mV    69.77uV
20ns      2.005nV    93.37nV    10.04nV
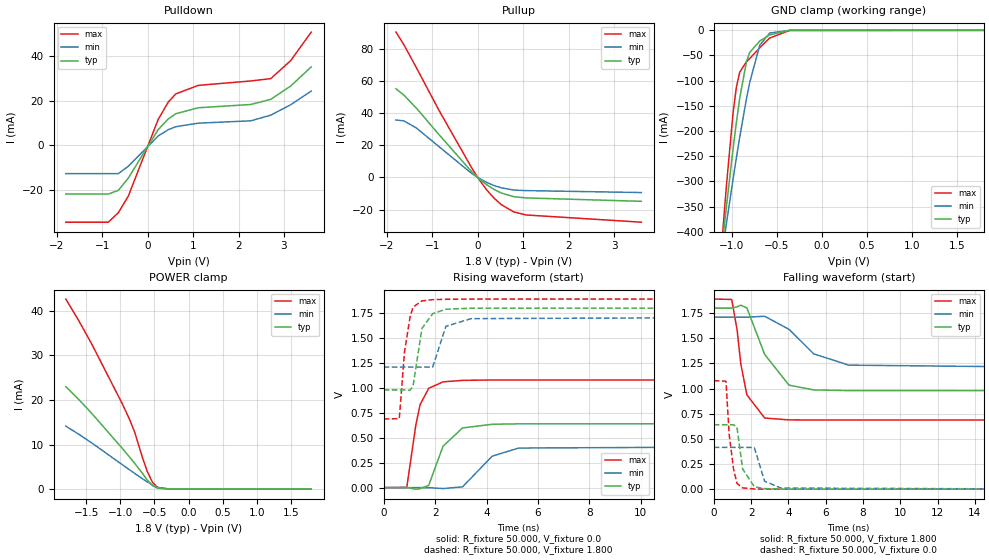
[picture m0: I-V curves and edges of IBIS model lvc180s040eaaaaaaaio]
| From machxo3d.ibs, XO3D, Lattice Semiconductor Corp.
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|   Model lvc180s040eaaaaaaaio
[Model] lvc180s040eaaaaaaaio
Model_type I/O
Polarity   Non-Inverting
Enable   Active-Low
Vinl =  0.630V
Vinh =  1.170V
Vmeas =  0.900V
Cref =  0.0F
Rref =  1.000M
Vref =  0.0V
C_comp   4.200pF   3.800pF   7.500pF
[Temperature Range]   25.000   0.105k   -40.000
[Voltage Range]   1.800V   1.710V   1.890V
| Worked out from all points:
|   slope of the pulldown table from 0 to 0.27 V, typ, clamps not added: 34 ohm
|   slope of the pullup table from 0 to 0.27 V, typ, clamps not added: 45.6 ohm
|   GND clamp passes 1 mA (typ) near -0.44 V on its own axis
|   POWER clamp passes 1 mA (typ) near -0.54 V on its own axis
|   rising waveform, R_fixture 50.000, V_fixture 0.0: 20-80 % time 626ps typ, 951ps min, 413ps max; typ from 0 V to 0.641 V
|   rising waveform, R_fixture 50.000, V_fixture 1.800: 20-80 % time 363ps typ, 366ps min, 304ps max; typ from 0.98 V to 1.8 V
|   falling waveform, R_fixture 50.000, V_fixture 1.800: 20-80 % time 1.1ns typ, 1.77ns min, 622ps max; typ from 1.8 V to 0.98 V
|   falling waveform, R_fixture 50.000, V_fixture 0.0: 20-80 % time 386ps typ, 402ps min, 324ps max; typ from 0.641 V to 0 V
[Pulldown]
|Voltage   I(typ)   I(min)   I(max)
-1.8V     -21.78mA   -12.65mA   -34.34mA
-865mV    -21.78mA   -12.65mA   -34.34mA
-645mV    -20.15mA   -12.65mA   -30.11mA
-425mV    -14.65mA   -9.378mA   -22.7mA
235mV     7.083mA    4.214mA    11.64mA
455mV     11.78mA    6.962mA    19.3mA
620mV     14.1mA     8.304mA    22.95mA
1.115V    16.77mA    9.887mA    26.76mA
2.27V     18.22mA    10.93mA    28.74mA
2.71V     20.53mA    13.47mA    29.77mA
3.15V     26.5mA     18.13mA    37.85mA
3.6V      35.01mA    24.22mA    50.56mA
[Pullup]
|Voltage   I(typ)   I(min)   I(max)
-1.8V     55.04mA    35.67mA    90.21mA
-1.625V   51.08mA    35.09mA    82.4mA
-1.35V    43.03mA    30.71mA    68.13mA
-855mV    26.68mA    19.18mA    41.78mA
-140mV    3.787mA    2.633mA    6.305mA
25mV      -631.9uA   -432.1uA   -1.07mA
190mV     -4.372mA   -2.969mA   -7.464mA
355mV     -7.378mA   -4.969mA   -12.72mA
520mV     -9.667mA   -6.446mA   -16.87mA
795mV     -11.95mA   -7.796mA   -21.4mA
1.07V     -12.7mA    -8.16mA    -23.29mA
3.6V      -14.81mA   -9.369mA   -27.76mA
[GND_clamp]
|Voltage   I(typ)   I(min)   I(max)
-1.8V     -1.677A    -1.372A    -2.207A
-1.097V   -411.6mA   -430.5mA   -392.9mA
-1.06V    -351mA     -384.7mA   -309.8mA
-986mV    -235.9mA   -295.9mA   -164.7mA
-949mV    -183mA     -253.4mA   -113mA
-912mV    -135mA     -212.5mA   -83.33mA
-838mV    -63.16mA   -137.2mA   -62.66mA
-801mV    -43.93mA   -103.8mA   -56.25mA
-690mV    -21.49mA   -30.06mA   -34.72mA
-579mV    -9.043mA   -5.343mA   -15.31mA
-357mV    -110.3uA   -52.32uA   -166.6uA
1.8V      0A         0A         0A
[POWER_clamp]
|Voltage   I(typ)   I(min)   I(max)
-1.8V     22.96mA    14.12mA    42.58mA
-1.604V   19.99mA    12.25mA    37.59mA
-1.419V   16.97mA    10.35mA    32.49mA
-975mV    9.199mA    5.527mA    19.24mA
-864mV    7.174mA    4.324mA    15.6mA
-790mV    5.788mA    3.534mA    12.79mA
-679mV    3.605mA    2.374mA    7.249mA
-605mV    2.066mA    1.631mA    3.958mA
-531mV    820.6uA    942.6uA    1.61mA
-457mV    221.3uA    381uA      405.2uA
-272mV    4.708uA    6.259uA    4.369uA
1.8V      0A         0A         4.229nA
[Ramp]
| variable   typ   min   max
dV/dt_r   0.384/0.627n   0.249/0.943n   0.647/0.409n
dV/dt_f   0.492/1.088n   0.301/1.761n   0.721/0.622n
R_load = 50.000
[Rising Waveform]
R_fixture= 50.000
V_fixture= 0.0
V_fixture_min= 0.0
V_fixture_max= 0.0
|time   V(typ)   V(min)   V(max)
0s        4.812nV    48.48nV    2.958nV
899ps     115.6uV    2.144uV    2.376mV
1.252ns   -15.47mV   117uV      630.1mV
1.417ns   -10.69mV   296.3uV    831.5mV
1.753ns   23.14mV    -614.5uV   995.8mV
2.309ns   415.2mV    -9.352mV   1.06V
3.067ns   598.2mV    7.636mV    1.075V
4.222ns   634.8mV    315.7mV    1.079V
5.248ns   639.4mV    396.6mV    1.079V
20ns      640.6mV    415.2mV    1.079V
[Rising Waveform]
R_fixture= 50.000
V_fixture= 1.800
V_fixture_min= 1.710
V_fixture_max= 1.890
|time   V(typ)   V(min)   V(max)
0s        979.8mV    1.209V     687.7mV
608ps     979.8mV    1.209V     691.8mV
809ps     979.8mV    1.209V     1.356V
1.024ns   974.3mV    1.209V     1.707V
1.143ns   1.018V     1.209V     1.809V
1.489ns   1.596V     1.209V     1.872V
1.907ns   1.744V     1.209V     1.884V
2.421ns   1.788V     1.617V     1.888V
3.404ns   1.798V     1.694V     1.89V
20ns      1.8V       1.71V      1.89V
[Falling Waveform]
R_fixture= 50.000
V_fixture= 1.800
V_fixture_min= 1.710
V_fixture_max= 1.890
|time   V(typ)   V(min)   V(max)
0s        1.8V       1.71V      1.89V
961ps     1.8V       1.71V      1.886V
1.253ns   1.813V     1.71V      1.58V
1.448ns   1.829V     1.71V      1.246V
1.775ns   1.802V     1.71V      937.6mV
2.731ns   1.339V     1.719V     707.3mV
4.035ns   1.034V     1.589V     688.6mV
5.363ns   986.7mV    1.345V     687.6mV
7.238ns   980.1mV    1.233V     687.7mV
20ns      979.8mV    1.209V     687.7mV
[Falling Waveform]
R_fixture= 50.000
V_fixture= 0.0
V_fixture_min= 0.0
V_fixture_max= 0.0
|time   V(typ)   V(min)   V(max)
0s        640.6mV    415.2mV    1.079V
654ps     640.6mV    415.2mV    1.073V
825ps     640.6mV    415.2mV    545.8mV
1.058ns   640.5mV    415.2mV    202.5mV
1.243ns   616.2mV    415.2mV    57.52mV
1.548ns   200.8mV    415.1mV    12.8mV
2.173ns   24.5mV     414.5mV    1.892mV
2.723ns   4.999mV    79.49mV    398.8uV
3.595ns   935.9uV    11.22mV    60.39uV
20ns      9.753nV    94.46nV    22.4nV
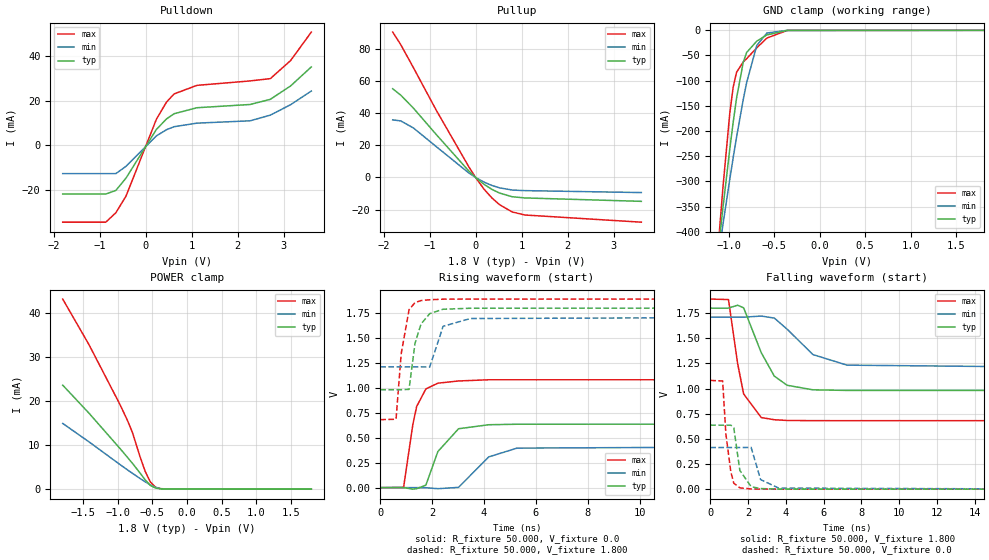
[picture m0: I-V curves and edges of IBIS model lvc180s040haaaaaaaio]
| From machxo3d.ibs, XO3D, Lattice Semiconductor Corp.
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|   Model lvc180s040haaaaaaaio
[Model] lvc180s040haaaaaaaio
Model_type I/O
Polarity   Non-Inverting
Enable   Active-Low
Vinl =  0.630V
Vinh =  1.170V
Vmeas =  0.900V
Cref =  0.0F
Rref =  1.000M
Vref =  0.0V
C_comp   4.200pF   3.800pF   7.500pF
[Temperature Range]   25.000   0.105k   -40.000
[Voltage Range]   1.800V   1.710V   1.890V
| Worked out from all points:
|   slope of the pulldown table from 0 to 0.27 V, typ, clamps not added: 34 ohm
|   slope of the pullup table from 0 to 0.27 V, typ, clamps not added: 45.6 ohm
|   GND clamp passes 1 mA (typ) near -0.44 V on its own axis
|   POWER clamp passes 1 mA (typ) near -0.54 V on its own axis
|   rising waveform, R_fixture 50.000, V_fixture 0.0: 20-80 % time 620ps typ, 965ps min, 424ps max; typ from 0 V to 0.636 V
|   rising waveform, R_fixture 50.000, V_fixture 1.800: 20-80 % time 361ps typ, 367ps min, 309ps max; typ from 0.981 V to 1.8 V
|   falling waveform, R_fixture 50.000, V_fixture 1.800: 20-80 % time 1.1ns typ, 1.76ns min, 632ps max; typ from 1.8 V to 0.981 V
|   falling waveform, R_fixture 50.000, V_fixture 0.0: 20-80 % time 376ps typ, 402ps min, 328ps max; typ from 0.636 V to 0 V
[Pulldown]
|Voltage   I(typ)   I(min)   I(max)
-1.8V     -21.78mA   -12.65mA   -34.34mA
-865mV    -21.78mA   -12.65mA   -34.34mA
-645mV    -20.15mA   -12.65mA   -30.11mA
-425mV    -14.65mA   -9.378mA   -22.7mA
235mV     7.083mA    4.214mA    11.64mA
455mV     11.78mA    6.962mA    19.3mA
620mV     14.1mA     8.304mA    22.95mA
1.115V    16.77mA    9.887mA    26.76mA
2.27V     18.22mA    10.93mA    28.74mA
2.71V     20.53mA    13.47mA    29.77mA
3.15V     26.5mA     18.13mA    37.84mA
3.6V      35mA       24.23mA    50.55mA
[Pullup]
|Voltage   I(typ)   I(min)   I(max)
-1.8V     55.06mA    35.72mA    90.22mA
-1.625V   51.09mA    35.11mA    82.4mA
-1.35V    43.03mA    30.72mA    68.13mA
-855mV    26.68mA    19.18mA    41.78mA
-140mV    3.787mA    2.633mA    6.305mA
25mV      -631.9uA   -432.1uA   -1.07mA
190mV     -4.372mA   -2.969mA   -7.464mA
355mV     -7.378mA   -4.969mA   -12.72mA
520mV     -9.667mA   -6.446mA   -16.87mA
795mV     -11.95mA   -7.796mA   -21.4mA
1.07V     -12.7mA    -8.16mA    -23.29mA
3.6V      -14.81mA   -9.369mA   -27.75mA
[GND_clamp]
|Voltage   I(typ)   I(min)   I(max)
-1.8V     -1.677A    -1.372A    -2.207A
-1.097V   -411.7mA   -430.5mA   -393mA
-1.06V    -351mA     -384.7mA   -309.9mA
-986mV    -235.9mA   -295.9mA   -164.8mA
-949mV    -183mA     -253.4mA   -113.1mA
-912mV    -135mA     -212.5mA   -83.39mA
-838mV    -63.2mA    -137.2mA   -62.73mA
-801mV    -43.97mA   -103.8mA   -56.32mA
-690mV    -21.54mA   -30.09mA   -34.79mA
-579mV    -9.102mA   -5.388mA   -15.4mA
-357mV    -191.3uA   -96.81uA   -298.1uA
1.8V      -12.41nA   0A         -10.91uA
[POWER_clamp]
|Voltage   I(typ)   I(min)   I(max)
-1.8V     23.65mA    14.95mA    43.22mA
-1.419V   17.27mA    10.75mA    32.84mA
-975mV    9.322mA    5.649mA    19.37mA
-864mV    7.265mA    4.408mA    15.69mA
-790mV    5.86mA     3.598mA    12.87mA
-679mV    3.655mA    2.417mA    7.32mA
-605mV    2.107mA    1.665mA    4.016mA
-531mV    854uA      968.7uA    1.658mA
-457mV    251.6uA    402uA      448.6uA
-383mV    77.17uA    103.3uA    115.3uA
-235mV    19.9uA     13.46uA    32.69uA
1.8V      0A         0A         0A
[Ramp]
| variable   typ   min   max
dV/dt_r   0.382/0.630n   0.248/0.933n   0.649/0.420n
dV/dt_f   0.491/1.089n   0.300/1.762n   0.725/0.634n
R_load = 50.000
[Rising Waveform]
R_fixture= 50.000
V_fixture= 0.0
V_fixture_min= 0.0
V_fixture_max= 0.0
|time   V(typ)   V(min)   V(max)
0s        4.637nV    47.96nV    2.735nV
899ps     113uV      2.075uV    2.593mV
1.257ns   -15.53mV   116.9uV    634.6mV
1.403ns   -10.99mV   295uV      813mV
1.758ns   24.88mV    -898uV     989.3mV
2.221ns   361.5mV    -10.83mV   1.047V
3.018ns   590.1mV    2.472mV    1.069V
4.181ns   630.3mV    307.7mV    1.081V
5.273ns   635.3mV    396mV      1.081V
20ns      636.4mV    413.8mV    1.081V
[Rising Waveform]
R_fixture= 50.000
V_fixture= 1.800
V_fixture_min= 1.710
V_fixture_max= 1.890
|time   V(typ)   V(min)   V(max)
0s        981.3mV    1.21V      681.2mV
608ps     981.3mV    1.21V      685.2mV
807ps     981.3mV    1.21V      1.342V
1.109ns   984.7mV    1.21V      1.783V
1.34ns    1.447V     1.21V      1.855V
1.573ns   1.641V     1.21V      1.875V
1.907ns   1.744V     1.209V     1.883V
2.422ns   1.788V     1.617V     1.889V
3.476ns   1.798V     1.695V     1.89V
20ns      1.8V       1.71V      1.89V
[Falling Waveform]
R_fixture= 50.000
V_fixture= 1.800
V_fixture_min= 1.710
V_fixture_max= 1.890
|time   V(typ)   V(min)   V(max)
0s        1.8V       1.71V      1.89V
963ps     1.8V       1.71V      1.885V
1.445ns   1.829V     1.71V      1.251V
1.765ns   1.803V     1.71V      947.3mV
2.695ns   1.358V     1.721V     711.9mV
3.388ns   1.124V     1.701V     690.3mV
4.064ns   1.033V     1.591V     683mV
5.433ns   987.7mV    1.338V     681.2mV
7.235ns   981.7mV    1.233V     681.1mV
20ns      981.3mV    1.21V      681.2mV
[Falling Waveform]
R_fixture= 50.000
V_fixture= 0.0
V_fixture_min= 0.0
V_fixture_max= 0.0
|time   V(typ)   V(min)   V(max)
0s        636.4mV    413.8mV    1.081V
654ps     636.4mV    413.8mV    1.076V
825ps     636.4mV    413.8mV    549.3mV
1.088ns   636.4mV    413.8mV    171mV
1.245ns   609.9mV    413.8mV    58.8mV
1.564ns   186.5mV    413.7mV    12.85mV
2.161ns   24.86mV    415.2mV    2.264mV
2.662ns   6.001mV    95.19mV    576.5uV
3.616ns   842.8uV    10.62mV    69.77uV
20ns      2.005nV    93.37nV    10.04nV
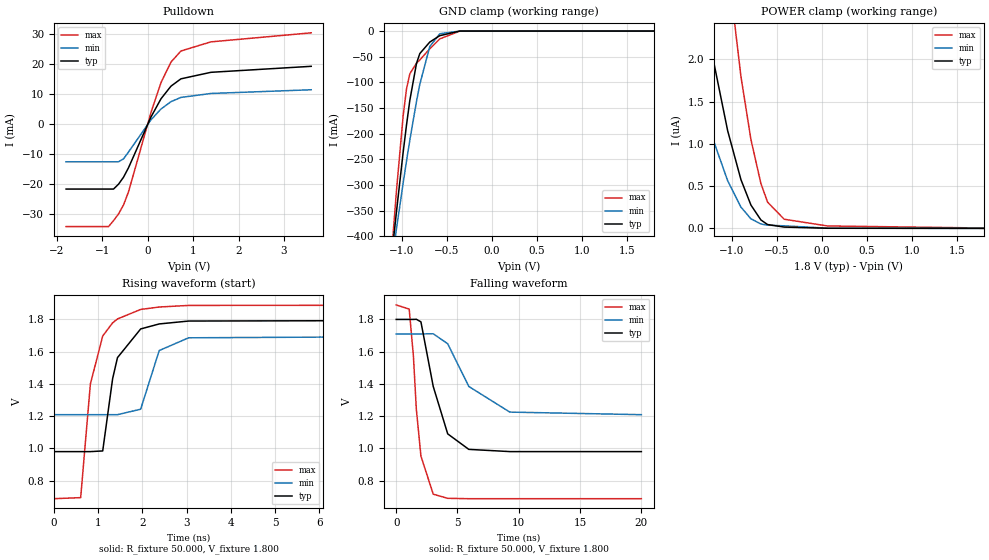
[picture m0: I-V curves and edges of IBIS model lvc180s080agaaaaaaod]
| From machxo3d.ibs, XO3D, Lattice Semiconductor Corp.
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|   Model lvc180s080agaaaaaaod
[Model] lvc180s080agaaaaaaod
Model_type I/O_open_drain
Polarity   Non-Inverting
Enable   Active-Low
Vinl =  0.630V
Vinh =  1.170V
Vmeas =  0.900V
Cref =  0.0F
Rref = 10.00k
Vref = 1.80V
C_comp   4.200pF   3.800pF   7.500pF
[Temperature Range]   25.000   0.105k   -40.000
[Voltage Range]   1.800V   1.710V   1.890V
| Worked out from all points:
|   slope of the pulldown table from 0 to 0.27 V, typ, clamps not added: 34 ohm
|   GND clamp passes 1 mA (typ) near -0.44 V on its own axis
|   rising waveform, R_fixture 50.000, V_fixture 1.800: 20-80 % time 346ps typ, 362ps min, 349ps max; typ from 0.98 V to 1.8 V
|   falling waveform, R_fixture 50.000, V_fixture 1.800: 20-80 % time 1.41ns typ, 2.35ns min, 773ps max; typ from 1.8 V to 0.98 V
[Pulldown]
|Voltage   I(typ)   I(min)   I(max)
-1.8V     -21.78mA   -12.65mA   -34.34mA
-865mV    -21.78mA   -12.65mA   -34.34mA
-755mV    -21.78mA   -12.65mA   -32.34mA
-645mV    -20.15mA   -12.65mA   -30.11mA
-535mV    -17.81mA   -11.66mA   -27.1mA
-425mV    -14.65mA   -9.378mA   -22.7mA
70mV      2.34mA     1.397mA    3.847mA
290mV     8.429mA    5.007mA    13.84mA
510mV     12.66mA    7.475mA    20.72mA
730mV     15.12mA    8.894mA    24.44mA
1.39V     17.3mA     10.22mA    27.49mA
3.6V      19.31mA    11.46mA    30.52mA
[GND_clamp]
|Voltage   I(typ)   I(min)   I(max)
-1.8V     -1.677A    -1.372A    -2.207A
-1.097V   -411.6mA   -430.5mA   -392.9mA
-1.06V    -351mA     -384.7mA   -309.8mA
-986mV    -235.9mA   -295.9mA   -164.7mA
-949mV    -183mA     -253.4mA   -113mA
-912mV    -135mA     -212.5mA   -83.33mA
-838mV    -63.16mA   -137.2mA   -62.66mA
-801mV    -43.93mA   -103.8mA   -56.25mA
-690mV    -21.49mA   -30.06mA   -34.72mA
-579mV    -9.043mA   -5.343mA   -15.31mA
-357mV    -110.3uA   -52.32uA   -166.6uA
1.8V      0A         0A         0A
[POWER_clamp]
|Voltage   I(typ)   I(min)   I(max)
-1.8V     6.918uA    4.075uA    15.53uA
-1.641V   5.335uA    3.081uA    12.17uA
-1.382V   3.16uA     1.741uA    7.507uA
-1.197V   1.931uA    1.01uA     4.843uA
-1.049V   1.156uA    564.3nA    3.128uA
-901mV    576.3nA    251.8nA    1.796uA
-790mV    276.2nA    113.3nA    1.051uA
-679mV    99.58nA    51.82nA    530.4nA
-605mV    45.37nA    37.94nA    310.9nA
-420mV    15.4nA     30.13nA    108.2nA
61mV      1.594nA    2.49nA     28.82nA
1.8V      0A         0A         4.229nA
[Ramp]
| variable   typ   min   max
dV/dt_r   0.492/0.345n   0.301/0.360n   0.721/0.348n
dV/dt_f   0.492/1.413n   0.301/2.351n   0.721/0.773n
R_load = 50.000
[Rising Waveform]
R_fixture= 50.000
V_fixture= 1.800
V_fixture_min= 1.710
V_fixture_max= 1.890
|time   V(typ)   V(min)   V(max)
0s        979.8mV    1.209V     687.7mV
607ps     979.8mV    1.209V     694.3mV
826ps     979.8mV    1.209V     1.399V
1.105ns   984mV      1.209V     1.697V
1.329ns   1.432V     1.209V     1.779V
1.439ns   1.563V     1.209V     1.803V
1.963ns   1.741V     1.243V     1.862V
2.382ns   1.772V     1.607V     1.877V
3.048ns   1.79V      1.686V     1.887V
20ns      1.8V       1.71V      1.89V
[Falling Waveform]
R_fixture= 50.000
V_fixture= 1.800
V_fixture_min= 1.710
V_fixture_max= 1.890
|time   V(typ)   V(min)   V(max)
0s        1.8V       1.71V      1.89V
1.06ns    1.8V       1.71V      1.864V
1.403ns   1.8V       1.71V      1.573V
1.64ns    1.801V     1.709V     1.245V
2.017ns   1.785V     1.71V      952mV
3.021ns   1.384V     1.711V     715.7mV
4.201ns   1.09V      1.649V     690mV
5.923ns   993.7mV    1.384V     687.7mV
9.267ns   980mV      1.225V     687.7mV
20ns      979.8mV    1.209V     687.7mV
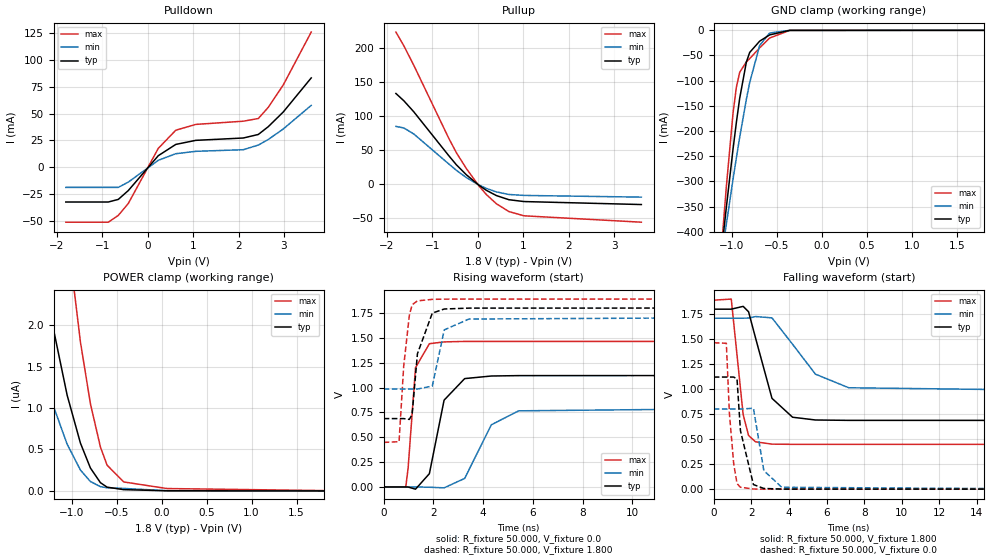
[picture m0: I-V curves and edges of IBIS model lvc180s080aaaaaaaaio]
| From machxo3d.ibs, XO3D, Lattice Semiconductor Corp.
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|   Model lvc180s080aaaaaaaaio
[Model] lvc180s080aaaaaaaaio
Model_type I/O
Polarity   Non-Inverting
Enable   Active-Low
Vinl =  0.630V
Vinh =  1.170V
Vmeas =  0.900V
Cref =  0.0F
Rref =  1.000M
Vref =  0.0V
C_comp   4.200pF   3.800pF   7.500pF
[Temperature Range]   25.000   0.105k   -40.000
[Voltage Range]   1.800V   1.710V   1.890V
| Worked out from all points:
|   slope of the pulldown table from 0 to 0.27 V, typ, clamps not added: 22.7 ohm
|   slope of the pullup table from 0 to 0.27 V, typ, clamps not added: 22.8 ohm
|   GND clamp passes 1 mA (typ) near -0.44 V on its own axis
|   rising waveform, R_fixture 50.000, V_fixture 0.0: 20-80 % time 564ps typ, 1.01ns min, 255ps max; typ from 0 V to 1.12 V
|   rising waveform, R_fixture 50.000, V_fixture 1.800: 20-80 % time 364ps typ, 365ps min, 290ps max; typ from 0.688 V to 1.8 V
|   falling waveform, R_fixture 50.000, V_fixture 1.800: 20-80 % time 957ps typ, 1.7ns min, 453ps max; typ from 1.8 V to 0.688 V
|   falling waveform, R_fixture 50.000, V_fixture 0.0: 20-80 % time 378ps typ, 403ps min, 307ps max; typ from 1.12 V to 0 V
[Pulldown]
|Voltage   I(typ)   I(min)   I(max)
-1.8V     -32.67mA   -18.98mA   -51.52mA
-865mV    -32.67mA   -18.98mA   -51.52mA
-645mV    -30.22mA   -18.98mA   -45.17mA
-425mV    -21.97mA   -14.07mA   -34.06mA
235mV     10.62mA    6.321mA    17.45mA
620mV     21.15mA    12.46mA    34.42mA
1.06V     24.95mA    14.7mA     39.84mA
2.105V    27.14mA    16.2mA     42.84mA
2.435V    30.43mA    20.53mA    45.35mA
2.655V    37.73mA    25.74mA    55.77mA
2.985V    51.46mA    35.61mA    76.72mA
3.6V      83.29mA    57.63mA    126.1mA
[Pullup]
|Voltage   I(typ)   I(min)   I(max)
-1.8V     133.3mA    85.05mA    223.4mA
-1.625V   122.6mA    82.74mA    203.2mA
-1.405V   106.3mA    73.8mA     174.4mA
-635mV    41.89mA    29.85mA    67.27mA
-470mV    28.72mA    20.63mA    46.43mA
-250mV    14.07mA    9.891mA    23.18mA
25mV      -1.264mA   -864.3uA   -2.139mA
190mV     -8.744mA   -5.939mA   -14.93mA
410mV     -16.44mA   -11.04mA   -28.45mA
685mV     -22.52mA   -14.83mA   -39.88mA
1.015V    -25.23mA   -16.24mA   -46.13mA
3.6V      -29.62mA   -18.74mA   -55.51mA
[GND_clamp]
|Voltage   I(typ)   I(min)   I(max)
-1.8V     -1.677A    -1.372A    -2.207A
-1.097V   -411.6mA   -430.5mA   -392.9mA
-1.06V    -351mA     -384.7mA   -309.8mA
-986mV    -235.9mA   -295.9mA   -164.7mA
-949mV    -183mA     -253.4mA   -113mA
-912mV    -135mA     -212.5mA   -83.33mA
-838mV    -63.16mA   -137.2mA   -62.66mA
-801mV    -43.93mA   -103.8mA   -56.25mA
-690mV    -21.49mA   -30.06mA   -34.72mA
-579mV    -9.043mA   -5.343mA   -15.31mA
-357mV    -110.3uA   -52.32uA   -166.6uA
1.8V      0A         0A         0A
[POWER_clamp]
|Voltage   I(typ)   I(min)   I(max)
-1.8V     6.918uA    4.075uA    15.53uA
-1.641V   5.335uA    3.081uA    12.17uA
-1.382V   3.16uA     1.741uA    7.507uA
-1.197V   1.931uA    1.01uA     4.843uA
-1.049V   1.156uA    564.3nA    3.128uA
-901mV    576.3nA    251.8nA    1.796uA
-790mV    276.2nA    113.2nA    1.051uA
-679mV    99.59nA    51.81nA    530.4nA
-605mV    45.39nA    37.93nA    310.9nA
-420mV    15.42nA    30.13nA    108.2nA
61mV      1.594nA    2.49nA     28.82nA
1.8V      0A         0A         4.229nA
[Ramp]
| variable   typ   min   max
dV/dt_r   0.673/0.562n   0.481/1.003n   0.878/0.253n
dV/dt_f   0.667/0.960n   0.435/1.700n   0.865/0.455n
R_load = 50.000
[Rising Waveform]
R_fixture= 50.000
V_fixture= 0.0
V_fixture_min= 0.0
V_fixture_max= 0.0
|time   V(typ)   V(min)   V(max)
0s        3.652nV    38.62nV    2.158nV
887ps     -46.08uV   1.777uV    -3.193mV
984ps     -923.1uV   1.777uV    190.4mV
1.281ns   -22.3mV    122.7uV    1.2V
1.838ns   133.4mV    -2.933mV   1.441V
2.429ns   873mV      -9.128mV   1.459V
3.257ns   1.09V      85.8mV     1.464V
4.329ns   1.116V     625.3mV    1.464V
5.426ns   1.12V      765.7mV    1.464V
20ns      1.121V     801mV      1.464V
[Rising Waveform]
R_fixture= 50.000
V_fixture= 1.800
V_fixture_min= 1.710
V_fixture_max= 1.890
|time   V(typ)   V(min)   V(max)
0s        687.7mV    984.9mV    448.1mV
619ps     687.7mV    984.9mV    455.1mV
806ps     687.6mV    984.9mV    1.215V
1.033ns   679.5mV    984.9mV    1.726V
1.144ns   729mV      984.7mV    1.832V
1.358ns   1.34V      984.5mV    1.872V
1.956ns   1.749V     1.015V     1.887V
2.436ns   1.79V      1.58V      1.889V
3.428ns   1.799V     1.689V     1.89V
20ns      1.8V       1.71V      1.89V
[Falling Waveform]
R_fixture= 50.000
V_fixture= 1.800
V_fixture_min= 1.710
V_fixture_max= 1.890
|time   V(typ)   V(min)   V(max)
0s        1.8V       1.71V      1.89V
930ps     1.8V       1.71V      1.901V
1.563ns   1.828V     1.71V      745mV
1.851ns   1.774V     1.711V     536.8mV
2.223ns   1.511V     1.726V     473.3mV
3.096ns   908.3mV    1.713V     450.3mV
4.192ns   719.4mV    1.449V     448.2mV
5.409ns   691.7mV    1.15V      448.1mV
7.181ns   688mV      1.014V     448.1mV
20ns      687.5mV    984.8mV    448.1mV
[Falling Waveform]
R_fixture= 50.000
V_fixture= 0.0
V_fixture_min= 0.0
V_fixture_max= 0.0
|time   V(typ)   V(min)   V(max)
0s        1.121V     801mV      1.464V
668ps     1.121V     801.1mV    1.459V
832ps     1.121V     801.1mV    754.6mV
1.06ns    1.121V     801mV      255.2mV
1.237ns   1.101V     801mV      55.27mV
1.418ns   585.8mV    801mV      19.28mV
2.109ns   45.92mV    808.9mV    1.869mV
2.663ns   7.12mV     185.6mV    387.3uV
3.616ns   999.5uV    18.75mV    56.8uV
20ns      60.36nV    98.59nV    15.78nV
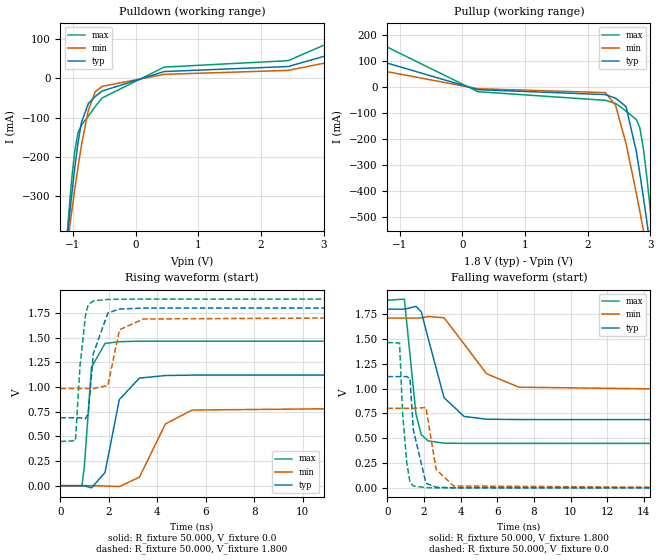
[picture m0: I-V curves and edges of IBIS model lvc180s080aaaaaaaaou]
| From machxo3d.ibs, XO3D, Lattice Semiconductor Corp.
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|   Model lvc180s080aaaaaaaaou
[Model] lvc180s080aaaaaaaaou
Model_type Output
Polarity   Non-Inverting
Enable   Active-High
Vmeas =  0.900V
Cref =  0.0F
Rref =  1.000M
Vref =  0.0V
C_comp   4.200pF   3.800pF   7.500pF
[Temperature Range]   25.000   0.105k   -40.000
[Voltage Range]   1.800V   1.710V   1.890V
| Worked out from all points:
|   slope of the pulldown table from 0 to 0.27 V, typ, clamps not added: 22.7 ohm
|   slope of the pullup table from 0 to 0.27 V, typ, clamps not added: 22.8 ohm
|   rising waveform, R_fixture 50.000, V_fixture 0.0: 20-80 % time 564ps typ, 1.01ns min, 255ps max; typ from 0 V to 1.12 V
|   rising waveform, R_fixture 50.000, V_fixture 1.800: 20-80 % time 364ps typ, 365ps min, 290ps max; typ from 0.688 V to 1.8 V
|   falling waveform, R_fixture 50.000, V_fixture 1.800: 20-80 % time 957ps typ, 1.7ns min, 453ps max; typ from 1.8 V to 0.688 V
|   falling waveform, R_fixture 50.000, V_fixture 0.0: 20-80 % time 378ps typ, 403ps min, 307ps max; typ from 1.12 V to 0 V
[Pulldown]
|Voltage   I(typ)   I(min)   I(max)
-1.8V     -1.678A    -1.373A    -2.208A
-1.085V   -398.1mA   -418.6mA   -380.8mA
-1.03V    -311.8mA   -351.7mA   -273.2mA
-975mV    -232.6mA   -287.4mA   -188.9mA
-920mV    -164.8mA   -226.6mA   -138.5mA
-865mV    -112.4mA   -170.7mA   -119.2mA
-755mV    -64.17mA   -81.42mA   -96.06mA
-645mV    -46.16mA   -34.1mA    -71.45mA
-535mV    -32.14mA   -20.1mA    -49.96mA
455mV     17.66mA    10.44mA    28.95mA
2.435V    30.43mA    20.53mA    45.35mA
3.6V      83.3mA     57.63mA    126.2mA
[Pullup]
|Voltage   I(typ)   I(min)   I(max)
-1.8V     133.3mA    85.05mA    223.4mA
245mV     -10.91mA   -7.39mA    -18.68mA
2.28V     -29.88mA   -22.22mA   -51.89mA
2.445V    -43.83mA   -71.95mA   -63.87mA
2.61V     -75.82mA   -217.6mA   -93.14mA
2.775V    -248.3mA   -409mA     -125.8mA
2.83V     -331.8mA   -477.6mA   -157mA
2.885V    -420.5mA   -547.6mA   -233.4mA
2.94V     -512.6mA   -618.9mA   -341.8mA
2.995V    -607.1mA   -691mA     -465.2mA
3.05V     -703.3mA   -763.9mA   -596.3mA
3.6V      -1.707A    -1.515A    -2.022A
[Ramp]
| variable   typ   min   max
dV/dt_r   0.673/0.562n   0.481/1.003n   0.878/0.253n
dV/dt_f   0.667/0.960n   0.435/1.700n   0.865/0.455n
R_load = 50.000
[Rising Waveform]
R_fixture= 50.000
V_fixture= 0.0
V_fixture_min= 0.0
V_fixture_max= 0.0
|time   V(typ)   V(min)   V(max)
0s        3.652nV    38.62nV    2.158nV
887ps     -46.08uV   1.777uV    -3.193mV
984ps     -923.1uV   1.777uV    190.4mV
1.281ns   -22.3mV    122.7uV    1.2V
1.838ns   133.4mV    -2.933mV   1.441V
2.429ns   873mV      -9.128mV   1.459V
3.257ns   1.09V      85.8mV     1.464V
4.329ns   1.116V     625.3mV    1.464V
5.426ns   1.12V      765.7mV    1.464V
20ns      1.121V     801mV      1.464V
[Rising Waveform]
R_fixture= 50.000
V_fixture= 1.800
V_fixture_min= 1.710
V_fixture_max= 1.890
|time   V(typ)   V(min)   V(max)
0s        687.7mV    984.9mV    448.1mV
619ps     687.7mV    984.9mV    455.1mV
806ps     687.6mV    984.9mV    1.215V
1.033ns   679.5mV    984.9mV    1.726V
1.144ns   729mV      984.7mV    1.832V
1.358ns   1.34V      984.5mV    1.872V
1.956ns   1.749V     1.015V     1.887V
2.436ns   1.79V      1.58V      1.889V
3.428ns   1.799V     1.689V     1.89V
20ns      1.8V       1.71V      1.89V
[Falling Waveform]
R_fixture= 50.000
V_fixture= 1.800
V_fixture_min= 1.710
V_fixture_max= 1.890
|time   V(typ)   V(min)   V(max)
0s        1.8V       1.71V      1.89V
930ps     1.8V       1.71V      1.901V
1.563ns   1.828V     1.71V      745mV
1.851ns   1.774V     1.711V     536.8mV
2.223ns   1.511V     1.726V     473.3mV
3.096ns   908.3mV    1.713V     450.3mV
4.192ns   719.4mV    1.449V     448.2mV
5.409ns   691.7mV    1.15V      448.1mV
7.181ns   688mV      1.014V     448.1mV
20ns      687.5mV    984.8mV    448.1mV
[Falling Waveform]
R_fixture= 50.000
V_fixture= 0.0
V_fixture_min= 0.0
V_fixture_max= 0.0
|time   V(typ)   V(min)   V(max)
0s        1.121V     801mV      1.464V
668ps     1.121V     801.1mV    1.459V
832ps     1.121V     801.1mV    754.6mV
1.06ns    1.121V     801mV      255.2mV
1.237ns   1.101V     801mV      55.27mV
1.418ns   585.8mV    801mV      19.28mV
2.109ns   45.92mV    808.9mV    1.869mV
2.663ns   7.12mV     185.6mV    387.3uV
3.616ns   999.5uV    18.75mV    56.8uV
20ns      60.36nV    98.59nV    15.78nV
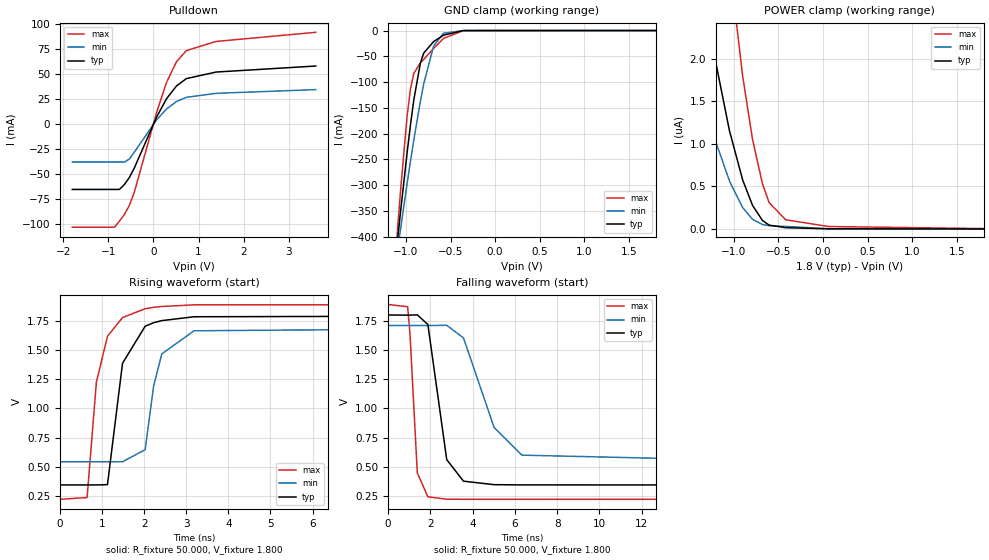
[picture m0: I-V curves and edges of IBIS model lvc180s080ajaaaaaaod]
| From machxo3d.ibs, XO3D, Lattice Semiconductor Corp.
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|   Model lvc180s080ajaaaaaaod
[Model] lvc180s080ajaaaaaaod
Model_type I/O_open_drain
Polarity   Non-Inverting
Enable   Active-Low
Vinl =  0.630V
Vinh =  1.170V
Vmeas =  0.900V
Cref =  0.0F
Rref = 10.00k
Vref = 1.80V
C_comp   4.200pF   3.800pF   7.500pF
[Temperature Range]   25.000   0.105k   -40.000
[Voltage Range]   1.800V   1.710V   1.890V
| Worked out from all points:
|   slope of the pulldown table from 0 to 0.27 V, typ, clamps not added: 11.3 ohm
|   GND clamp passes 1 mA (typ) near -0.44 V on its own axis
|   rising waveform, R_fixture 50.000, V_fixture 1.800: 20-80 % time 342ps typ, 353ps min, 350ps max; typ from 0.345 V to 1.8 V
|   falling waveform, R_fixture 50.000, V_fixture 1.800: 20-80 % time 628ps typ, 1.43ns min, 278ps max; typ from 1.8 V to 0.345 V
[Pulldown]
|Voltage   I(typ)   I(min)   I(max)
-1.8V     -65.34mA   -37.96mA   -103mA
-865mV    -65.34mA   -37.96mA   -103mA
-755mV    -65.34mA   -37.96mA   -97.01mA
-645mV    -60.44mA   -37.96mA   -90.34mA
-535mV    -53.42mA   -34.97mA   -81.29mA
-425mV    -43.95mA   -28.13mA   -68.11mA
70mV      7.021mA    4.191mA    11.54mA
290mV     25.29mA    15.02mA    41.53mA
510mV     37.99mA    22.42mA    62.15mA
730mV     45.35mA    26.68mA    73.32mA
1.39V     51.91mA    30.65mA    82.47mA
3.6V      57.92mA    34.37mA    91.57mA
[GND_clamp]
|Voltage   I(typ)   I(min)   I(max)
-1.8V     -1.677A    -1.372A    -2.207A
-1.097V   -411.6mA   -430.5mA   -392.9mA
-1.06V    -351mA     -384.7mA   -309.8mA
-986mV    -235.9mA   -295.9mA   -164.7mA
-949mV    -183mA     -253.4mA   -113mA
-912mV    -135mA     -212.5mA   -83.33mA
-838mV    -63.16mA   -137.2mA   -62.66mA
-801mV    -43.93mA   -103.8mA   -56.25mA
-690mV    -21.49mA   -30.06mA   -34.72mA
-579mV    -9.043mA   -5.343mA   -15.31mA
-357mV    -110.3uA   -52.32uA   -166.6uA
1.8V      0A         0A         0A
[POWER_clamp]
|Voltage   I(typ)   I(min)   I(max)
-1.8V     6.918uA    4.075uA    15.53uA
-1.641V   5.335uA    3.081uA    12.17uA
-1.382V   3.16uA     1.741uA    7.507uA
-1.197V   1.931uA    1.01uA     4.843uA
-1.049V   1.156uA    564.3nA    3.128uA
-901mV    576.3nA    251.8nA    1.796uA
-790mV    276.2nA    113.2nA    1.051uA
-679mV    99.6nA     51.81nA    530.4nA
-605mV    45.39nA    37.93nA    310.9nA
-420mV    15.42nA    30.12nA    108.3nA
61mV      1.594nA    2.49nA     28.82nA
1.8V      0A         0A         4.229nA
[Ramp]
| variable   typ   min   max
dV/dt_r   0.873/0.341n   0.700/0.353n   1.001/0.346n
dV/dt_f   0.873/0.629n   0.700/1.405n   1.001/0.277n
R_load = 50.000
[Rising Waveform]
R_fixture= 50.000
V_fixture= 1.800
V_fixture_min= 1.710
V_fixture_max= 1.890
|time   V(typ)   V(min)   V(max)
0s        345mV      543mV      221.8mV
641ps     345mV      543mV      237.2mV
861ps     345mV      543mV      1.224V
1.125ns   347.6mV    542.9mV    1.618V
1.483ns   1.387V     543.1mV    1.778V
2.021ns   1.704V     647.2mV    1.854V
2.223ns   1.734V     1.193V     1.866V
2.417ns   1.752V     1.467V     1.873V
3.183ns   1.785V     1.665V     1.887V
20ns      1.8V       1.71V      1.89V
[Falling Waveform]
R_fixture= 50.000
V_fixture= 1.800
V_fixture_min= 1.710
V_fixture_max= 1.890
|time   V(typ)   V(min)   V(max)
0s        1.8V       1.71V      1.89V
926ps     1.799V     1.71V      1.871V
1.036ns   1.799V     1.71V      1.64V
1.383ns   1.801V     1.71V      448.4mV
1.883ns   1.719V     1.71V      243mV
2.775ns   561.6mV    1.712V     223.3mV
3.568ns   377.2mV    1.604V     221.9mV
5.015ns   347.4mV    837.7mV    221.8mV
6.333ns   345.3mV    600.1mV    221.8mV
20ns      345mV      542.9mV    221.8mV
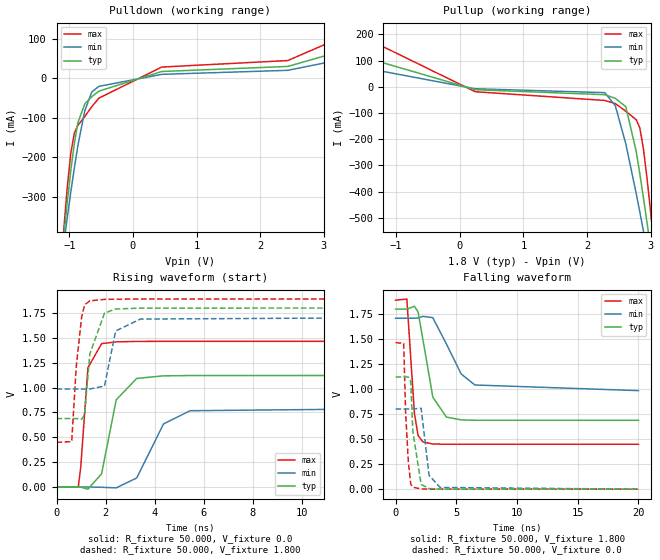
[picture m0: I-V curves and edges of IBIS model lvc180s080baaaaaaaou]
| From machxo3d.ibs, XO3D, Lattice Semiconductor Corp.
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|   Model lvc180s080baaaaaaaou
[Model] lvc180s080baaaaaaaou
Model_type Output
Polarity   Non-Inverting
Enable   Active-High
Vmeas =  0.900V
Cref =  0.0F
Rref =  1.000M
Vref =  0.0V
C_comp   4.200pF   3.800pF   7.500pF
[Temperature Range]   25.000   0.105k   -40.000
[Voltage Range]   1.800V   1.710V   1.890V
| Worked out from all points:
|   slope of the pulldown table from 0 to 0.27 V, typ, clamps not added: 22.7 ohm
|   slope of the pullup table from 0 to 0.27 V, typ, clamps not added: 22.8 ohm
|   rising waveform, R_fixture 50.000, V_fixture 0.0: 20-80 % time 562ps typ, 1ns min, 254ps max; typ from 0.001 V to 1.12 V
|   rising waveform, R_fixture 50.000, V_fixture 1.800: 20-80 % time 365ps typ, 362ps min, 288ps max; typ from 0.689 V to 1.8 V
|   falling waveform, R_fixture 50.000, V_fixture 1.800: 20-80 % time 963ps typ, 1.72ns min, 455ps max; typ from 1.8 V to 0.689 V
|   falling waveform, R_fixture 50.000, V_fixture 0.0: 20-80 % time 381ps typ, 403ps min, 308ps max; typ from 1.12 V to 0.001 V
[Pulldown]
|Voltage   I(typ)   I(min)   I(max)
-1.8V     -1.678A    -1.373A    -2.208A
-1.085V   -398.1mA   -418.6mA   -380.8mA
-1.03V    -311.8mA   -351.7mA   -273.2mA
-975mV    -232.6mA   -287.4mA   -189mA
-920mV    -164.8mA   -226.6mA   -138.6mA
-865mV    -112.4mA   -170.8mA   -119.3mA
-755mV    -64.19mA   -81.42mA   -96.09mA
-645mV    -46.18mA   -34.11mA   -71.49mA
-535mV    -32.16mA   -20.11mA   -50.01mA
455mV     17.62mA    10.42mA    28.87mA
2.435V    30.47mA    20.58mA    45.4mA
3.6V      83.98mA    58.61mA    126.7mA
[Pullup]
|Voltage   I(typ)   I(min)   I(max)
-1.8V     134mA      85.95mA    224mA
245mV     -10.92mA   -7.399mA   -18.71mA
2.28V     -29.91mA   -22.24mA   -51.96mA
2.445V    -43.84mA   -71.96mA   -63.91mA
2.61V     -75.83mA   -217.6mA   -93.16mA
2.775V    -248.3mA   -409mA     -125.8mA
2.83V     -331.8mA   -477.6mA   -157mA
2.885V    -420.5mA   -547.7mA   -233.4mA
2.94V     -512.7mA   -618.9mA   -341.9mA
2.995V    -607.1mA   -691mA     -465.2mA
3.05V     -703.3mA   -763.9mA   -596.3mA
3.6V      -1.707A    -1.515A    -2.022A
[Ramp]
| variable   typ   min   max
dV/dt_r   0.673/0.561n   0.481/1.003n   0.878/0.253n
dV/dt_f   0.667/0.963n   0.435/1.689n   0.864/0.456n
R_load = 50.000
[Rising Waveform]
R_fixture= 50.000
V_fixture= 0.0
V_fixture_min= 0.0
V_fixture_max= 0.0
|time   V(typ)   V(min)   V(max)
0s        542.4uV    393.2uV    769.5uV
887ps     445.8uV    419.5uV    -445.5uV
985ps     -400.9uV   394.5uV    196.5mV
1.28ns    -21.38mV   518.1uV    1.2V
1.837ns   133.9mV    -2.453mV   1.442V
2.433ns   877.4mV    -8.163mV   1.46V
3.267ns   1.092V     91.18mV    1.464V
4.361ns   1.118V     634.7mV    1.465V
5.444ns   1.121V     767.5mV    1.465V
20ns      1.122V     801.9mV    1.465V
[Rising Waveform]
R_fixture= 50.000
V_fixture= 1.800
V_fixture_min= 1.710
V_fixture_max= 1.890
|time   V(typ)   V(min)   V(max)
0s        688.8mV    985.7mV    449.4mV
619ps     688.9mV    985.7mV    456.5mV
804ps     688.8mV    985.7mV    1.212V
1.025ns   681.8mV    985.7mV    1.712V
1.143ns   728.6mV    985.6mV    1.832V
1.356ns   1.338V     985.4mV    1.872V
1.956ns   1.749V     1.016V     1.887V
2.409ns   1.79V      1.569V     1.889V
3.417ns   1.799V     1.689V     1.89V
20ns      1.8V       1.71V      1.89V
[Falling Waveform]
R_fixture= 50.000
V_fixture= 1.800
V_fixture_min= 1.710
V_fixture_max= 1.890
|time   V(typ)   V(min)   V(max)
0s        1.8V       1.71V      1.89V
930ps     1.8V       1.71V      1.901V
1.557ns   1.829V     1.71V      755.4mV
1.856ns   1.772V     1.711V     536.8mV
2.251ns   1.497V     1.728V     472.8mV
3.068ns   921.1mV    1.715V     451.8mV
4.18ns    721.3mV    1.453V     449.5mV
5.405ns   692.9mV    1.152V     449.4mV
6.527ns   689.5mV    1.042V     449.4mV
20ns      688.8mV    985.6mV    449.3mV
[Falling Waveform]
R_fixture= 50.000
V_fixture= 0.0
V_fixture_min= 0.0
V_fixture_max= 0.0
|time   V(typ)   V(min)   V(max)
0s        1.122V     801.9mV    1.465V
668ps     1.122V     801.9mV    1.459V
832ps     1.122V     801.9mV    757.1mV
1.049ns   1.122V     801.9mV    280.1mV
1.253ns   1.077V     801.9mV    50.43mV
1.422ns   578.1mV    801.9mV    19.9mV
2.107ns   47.65mV    809.8mV    2.856mV
2.76ns    6.412mV    138.2mV    1.121mV
3.671ns   1.454mV    17.4mV     815.9uV
20ns      542.5uV    393.3uV    769.4uV
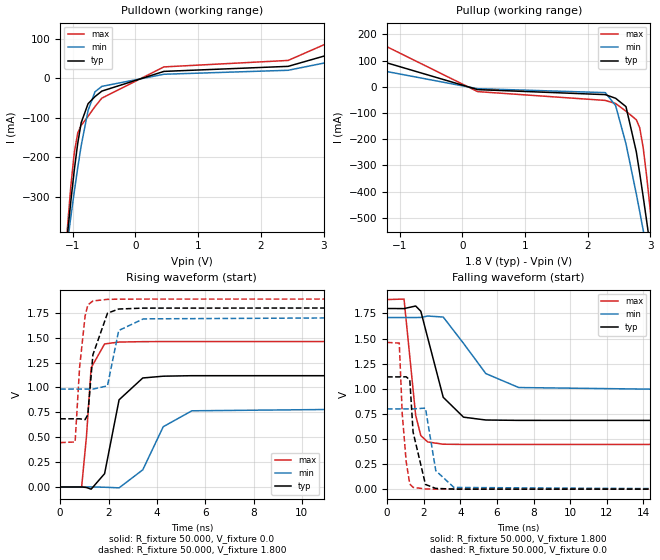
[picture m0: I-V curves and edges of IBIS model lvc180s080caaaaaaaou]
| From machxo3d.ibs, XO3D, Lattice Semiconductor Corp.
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|   Model lvc180s080caaaaaaaou
[Model] lvc180s080caaaaaaaou
Model_type Output
Polarity   Non-Inverting
Enable   Active-High
Vmeas =  0.900V
Cref =  0.0F
Rref =  1.000M
Vref =  0.0V
C_comp   4.200pF   3.800pF   7.500pF
[Temperature Range]   25.000   0.105k   -40.000
[Voltage Range]   1.800V   1.710V   1.890V
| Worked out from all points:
|   slope of the pulldown table from 0 to 0.27 V, typ, clamps not added: 22.6 ohm
|   slope of the pullup table from 0 to 0.27 V, typ, clamps not added: 22.8 ohm
|   rising waveform, R_fixture 50.000, V_fixture 0.0: 20-80 % time 563ps typ, 1.02ns min, 256ps max; typ from 0 V to 1.12 V
|   rising waveform, R_fixture 50.000, V_fixture 1.800: 20-80 % time 369ps typ, 364ps min, 291ps max; typ from 0.685 V to 1.8 V
|   falling waveform, R_fixture 50.000, V_fixture 1.800: 20-80 % time 960ps typ, 1.7ns min, 452ps max; typ from 1.8 V to 0.685 V
|   falling waveform, R_fixture 50.000, V_fixture 0.0: 20-80 % time 372ps typ, 400ps min, 302ps max; typ from 1.12 V to 0 V
[Pulldown]
|Voltage   I(typ)   I(min)   I(max)
-1.8V     -1.678A    -1.373A    -2.208A
-1.085V   -398.1mA   -418.6mA   -380.8mA
-1.03V    -311.9mA   -351.7mA   -273.3mA
-975mV    -232.6mA   -287.4mA   -189mA
-920mV    -164.8mA   -226.7mA   -138.6mA
-865mV    -112.5mA   -170.8mA   -119.3mA
-755mV    -64.22mA   -81.44mA   -96.13mA
-645mV    -46.21mA   -34.14mA   -71.53mA
-535mV    -32.2mA    -20.15mA   -50.06mA
455mV     17.74mA    10.47mA    29.12mA
2.435V    30.5mA     20.56mA    45.5mA
3.6V      83.46mA    57.71mA    126.5mA
[Pullup]
|Voltage   I(typ)   I(min)   I(max)
-1.8V     133.4mA    85.13mA    223.7mA
245mV     -10.81mA   -7.353mA   -18.44mA
2.28V     -29.95mA   -22.26mA   -52.02mA
2.445V    -43.86mA   -71.97mA   -63.95mA
2.61V     -75.85mA   -217.6mA   -93.19mA
2.775V    -248.3mA   -409mA     -125.8mA
2.83V     -331.8mA   -477.6mA   -157mA
2.885V    -420.5mA   -547.7mA   -233.5mA
2.94V     -512.7mA   -618.9mA   -341.9mA
2.995V    -607.1mA   -691mA     -465.3mA
3.05V     -703.3mA   -763.9mA   -596.3mA
3.6V      -1.707A    -1.515A    -2.022A
[Ramp]
| variable   typ   min   max
dV/dt_r   0.671/0.563n   0.480/1.004n   0.876/0.254n
dV/dt_f   0.668/0.959n   0.436/1.693n   0.865/0.453n
R_load = 50.000
[Rising Waveform]
R_fixture= 50.000
V_fixture= 0.0
V_fixture_min= 0.0
V_fixture_max= 0.0
|time   V(typ)   V(min)   V(max)
0s        3.523nV    38.23nV    1.999nV
887ps     -48.08uV   1.728uV    -2.853mV
1.088ns   -5.443mV   1.728uV    506.5mV
1.282ns   -22.25mV   123.7uV    1.198V
1.838ns   133.4mV    -2.93mV    1.437V
2.437ns   875.8mV    -8.918mV   1.456V
3.417ns   1.095V     172.1mV    1.46V
4.263ns   1.113V     605.1mV    1.461V
5.447ns   1.118V     765.2mV    1.461V
20ns      1.118V     799.4mV    1.461V
[Rising Waveform]
R_fixture= 50.000
V_fixture= 1.800
V_fixture_min= 1.710
V_fixture_max= 1.890
|time   V(typ)   V(min)   V(max)
0s        684.9mV    983.3mV    445.4mV
619ps     684.9mV    983.3mV    452.2mV
803ps     684.8mV    983.3mV    1.199V
1.032ns   676.8mV    983.3mV    1.718V
1.144ns   726.1mV    983.2mV    1.829V
1.354ns   1.328V     983mV      1.869V
1.958ns   1.746V     1.016V     1.885V
2.421ns   1.788V     1.572V     1.887V
3.441ns   1.797V     1.689V     1.888V
20ns      1.799V     1.709V     1.888V
[Falling Waveform]
R_fixture= 50.000
V_fixture= 1.800
V_fixture_min= 1.710
V_fixture_max= 1.890
|time   V(typ)   V(min)   V(max)
0s        1.799V     1.709V     1.888V
929ps     1.798V     1.709V     1.893V
1.564ns   1.824V     1.709V     735.2mV
1.845ns   1.772V     1.71V      533.4mV
2.222ns   1.507V     1.724V     470.1mV
3.069ns   914.8mV    1.714V     447.7mV
4.177ns   716.9mV    1.452V     445.5mV
5.396ns   688.7mV    1.151V     445.4mV
7.193ns   685mV      1.012V     445.4mV
20ns      684.6mV    983.3mV    445.4mV
[Falling Waveform]
R_fixture= 50.000
V_fixture= 0.0
V_fixture_min= 0.0
V_fixture_max= 0.0
|time   V(typ)   V(min)   V(max)
0s        1.118V     799.4mV    1.461V
668ps     1.118V     799.5mV    1.455V
832ps     1.118V     799.5mV    746.8mV
1.047ns   1.119V     799.5mV    272.5mV
1.244ns   1.088V     799.5mV    50.19mV
1.424ns   567.8mV    799.5mV    18.08mV
2.099ns   46.79mV    807mV      1.859mV
2.663ns   7.496mV    184.2mV    383.1uV
3.655ns   941.3uV    16.95mV    55.46uV
20ns      53.29nV    95.61nV    3.362nV
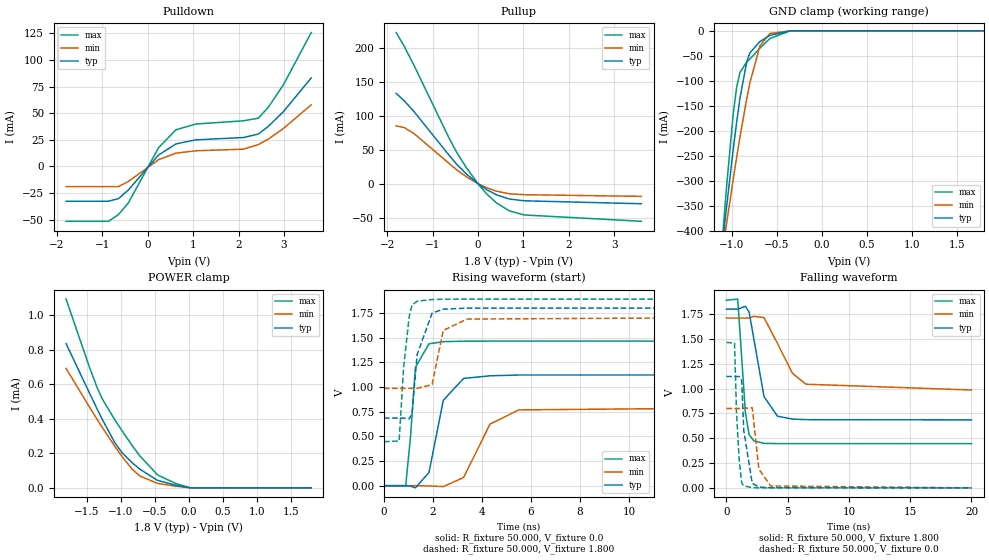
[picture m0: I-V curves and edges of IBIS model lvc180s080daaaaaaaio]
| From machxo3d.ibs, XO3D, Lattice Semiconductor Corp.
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|   Model lvc180s080daaaaaaaio
[Model] lvc180s080daaaaaaaio
Model_type I/O
Polarity   Non-Inverting
Enable   Active-Low
Vinl =  0.630V
Vinh =  1.170V
Vmeas =  0.900V
Cref =  0.0F
Rref =  1.000M
Vref =  0.0V
C_comp   4.200pF   3.800pF   7.500pF
[Temperature Range]   25.000   0.105k   -40.000
[Voltage Range]   1.800V   1.710V   1.890V
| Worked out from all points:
|   slope of the pulldown table from 0 to 0.27 V, typ, clamps not added: 22.7 ohm
|   slope of the pullup table from 0 to 0.27 V, typ, clamps not added: 22.8 ohm
|   GND clamp passes 1 mA (typ) near -0.44 V on its own axis
|   rising waveform, R_fixture 50.000, V_fixture 0.0: 20-80 % time 570ps typ, 1.01ns min, 255ps max; typ from 0 V to 1.12 V
|   rising waveform, R_fixture 50.000, V_fixture 1.800: 20-80 % time 370ps typ, 363ps min, 291ps max; typ from 0.685 V to 1.8 V
|   falling waveform, R_fixture 50.000, V_fixture 1.800: 20-80 % time 971ps typ, 1.72ns min, 458ps max; typ from 1.8 V to 0.685 V
|   falling waveform, R_fixture 50.000, V_fixture 0.0: 20-80 % time 381ps typ, 401ps min, 308ps max; typ from 1.12 V to 0 V
[Pulldown]
|Voltage   I(typ)   I(min)   I(max)
-1.8V     -32.67mA   -18.98mA   -51.52mA
-865mV    -32.67mA   -18.98mA   -51.52mA
-645mV    -30.22mA   -18.98mA   -45.17mA
-425mV    -21.97mA   -14.07mA   -34.06mA
235mV     10.62mA    6.321mA    17.45mA
620mV     21.15mA    12.46mA    34.42mA
1.06V     24.95mA    14.7mA     39.84mA
2.105V    27.14mA    16.2mA     42.84mA
2.435V    30.39mA    20.51mA    45.29mA
2.655V    37.67mA    25.68mA    55.62mA
2.985V    51.32mA    35.55mA    76.49mA
3.6V      83.14mA    57.86mA    125.7mA
[Pullup]
|Voltage   I(typ)   I(min)   I(max)
-1.8V     133.2mA    85.25mA    222.9mA
-1.625V   122.4mA    82.83mA    202.8mA
-1.405V   106.1mA    73.78mA    174.1mA
-635mV    41.85mA    29.84mA    67.18mA
-470mV    28.7mA     20.63mA    46.39mA
-250mV    14.07mA    9.891mA    23.18mA
25mV      -1.264mA   -864.3uA   -2.139mA
190mV     -8.744mA   -5.939mA   -14.93mA
410mV     -16.44mA   -11.04mA   -28.45mA
685mV     -22.52mA   -14.83mA   -39.88mA
1.015V    -25.23mA   -16.24mA   -46.13mA
3.6V      -29.62mA   -18.74mA   -55.5mA
[GND_clamp]
|Voltage   I(typ)   I(min)   I(max)
-1.8V     -1.677A    -1.372A    -2.207A
-1.097V   -411.7mA   -430.5mA   -393mA
-1.06V    -351mA     -384.7mA   -309.9mA
-986mV    -235.9mA   -295.9mA   -164.8mA
-949mV    -183mA     -253.4mA   -113.1mA
-912mV    -135mA     -212.5mA   -83.39mA
-838mV    -63.2mA    -137.2mA   -62.73mA
-801mV    -43.97mA   -103.8mA   -56.32mA
-690mV    -21.54mA   -30.09mA   -34.79mA
-579mV    -9.102mA   -5.388mA   -15.4mA
-357mV    -191.3uA   -96.81uA   -298.1uA
1.8V      -12.41nA   0A         -10.91uA
[POWER_clamp]
|Voltage   I(typ)   I(min)   I(max)
-1.8V     836.1uA    692.5uA    1.094mA
-1.456V   549uA      467.8uA    698.7uA
-1.345V   458uA      397.8uA    582.4uA
-1.271V   398.7uA    352uA      517.3uA
-1.086V   262.9uA    241.7uA    395.6uA
-975mV    202uA      179.8uA    328.7uA
-827mV    144.5uA    107.4uA    243.8uA
-716mV    108uA      68.49uA    184.9uA
-457mV    43.42uA    25.76uA    75.17uA
-198mV    15.77uA    10.09uA    26.67uA
24mV      0A         0A         0A
1.8V      0A         0A         0A
[Ramp]
| variable   typ   min   max
dV/dt_r   0.673/0.567n   0.480/1.004n   0.879/0.256n
dV/dt_f   0.669/0.967n   0.435/1.693n   0.867/0.458n
R_load = 50.000
[Rising Waveform]
R_fixture= 50.000
V_fixture= 0.0
V_fixture_min= 0.0
V_fixture_max= 0.0
|time   V(typ)   V(min)   V(max)
0s        3.523nV    38.23nV    1.999nV
887ps     -48.08uV   1.634uV    -2.853mV
1.088ns   -5.443mV   1.634uV    506.5mV
1.282ns   -22.25mV   122.5uV    1.198V
1.838ns   133.4mV    -2.93mV    1.437V
2.422ns   865mV      -9.226mV   1.459V
3.25ns    1.087V     82.39mV    1.464V
4.329ns   1.113V     624mV      1.465V
5.502ns   1.121V     767.6mV    1.465V
20ns      1.122V     799.4mV    1.465V
[Rising Waveform]
R_fixture= 50.000
V_fixture= 1.800
V_fixture_min= 1.710
V_fixture_max= 1.890
|time   V(typ)   V(min)   V(max)
0s        684.9mV    985.7mV    445.4mV
619ps     684.9mV    985.7mV    452.2mV
803ps     684.8mV    985.7mV    1.199V
1.032ns   676.8mV    985.7mV    1.718V
1.144ns   726.1mV    985.6mV    1.829V
1.354ns   1.328V     985.3mV    1.869V
1.964ns   1.748V     1.024V     1.886V
2.419ns   1.788V     1.573V     1.889V
3.395ns   1.799V     1.688V     1.89V
20ns      1.8V       1.71V      1.89V
[Falling Waveform]
R_fixture= 50.000
V_fixture= 1.800
V_fixture_min= 1.710
V_fixture_max= 1.890
|time   V(typ)   V(min)   V(max)
0s        1.8V       1.71V      1.89V
930ps     1.8V       1.71V      1.901V
1.557ns   1.829V     1.71V      755.4mV
1.856ns   1.772V     1.711V     536.8mV
2.251ns   1.497V     1.728V     472.8mV
3.074ns   918.6mV    1.715V     448.2mV
4.18ns    721.3mV    1.453V     445.5mV
5.405ns   692.9mV    1.152V     445.4mV
6.497ns   686.9mV    1.044V     445.4mV
20ns      684.8mV    985.6mV    445.3mV
[Falling Waveform]
R_fixture= 50.000
V_fixture= 0.0
V_fixture_min= 0.0
V_fixture_max= 0.0
|time   V(typ)   V(min)   V(max)
0s        1.122V     799.4mV    1.465V
668ps     1.122V     799.5mV    1.459V
832ps     1.122V     799.5mV    757.1mV
1.049ns   1.122V     799.5mV    280.1mV
1.253ns   1.077V     799.5mV    50.43mV
1.422ns   578.1mV    799.5mV    19.9mV
2.114ns   46.18mV    807.5mV    2.035mV
2.654ns   8.088mV    189.7mV    461.2uV
3.609ns   1.313mV    18.77mV    80.54uV
20ns      59.11nV    95.61nV    6.244nV
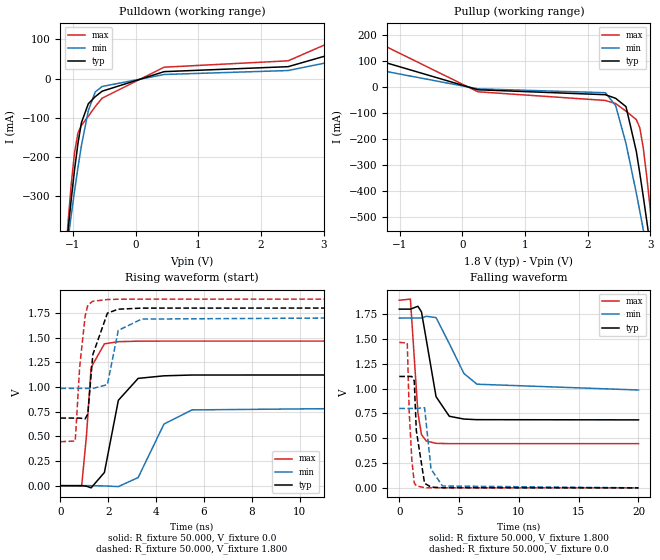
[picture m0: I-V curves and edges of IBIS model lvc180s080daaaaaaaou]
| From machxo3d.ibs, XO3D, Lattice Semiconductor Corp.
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|   Model lvc180s080daaaaaaaou
[Model] lvc180s080daaaaaaaou
Model_type Output
Polarity   Non-Inverting
Enable   Active-High
Vmeas =  0.900V
Cref =  0.0F
Rref =  1.000M
Vref =  0.0V
C_comp   4.200pF   3.800pF   7.500pF
[Temperature Range]   25.000   0.105k   -40.000
[Voltage Range]   1.800V   1.710V   1.890V
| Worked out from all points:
|   slope of the pulldown table from 0 to 0.27 V, typ, clamps not added: 22.6 ohm
|   slope of the pullup table from 0 to 0.27 V, typ, clamps not added: 22.8 ohm
|   rising waveform, R_fixture 50.000, V_fixture 0.0: 20-80 % time 570ps typ, 1.01ns min, 255ps max; typ from 0 V to 1.12 V
|   rising waveform, R_fixture 50.000, V_fixture 1.800: 20-80 % time 370ps typ, 363ps min, 291ps max; typ from 0.685 V to 1.8 V
|   falling waveform, R_fixture 50.000, V_fixture 1.800: 20-80 % time 971ps typ, 1.72ns min, 458ps max; typ from 1.8 V to 0.685 V
|   falling waveform, R_fixture 50.000, V_fixture 0.0: 20-80 % time 381ps typ, 401ps min, 308ps max; typ from 1.12 V to 0 V
[Pulldown]
|Voltage   I(typ)   I(min)   I(max)
-1.8V     -1.678A    -1.373A    -2.208A
-1.085V   -398.1mA   -418.6mA   -380.8mA
-1.03V    -311.9mA   -351.7mA   -273.3mA
-975mV    -232.6mA   -287.4mA   -189mA
-920mV    -164.8mA   -226.7mA   -138.6mA
-865mV    -112.5mA   -170.8mA   -119.3mA
-755mV    -64.22mA   -81.44mA   -96.13mA
-645mV    -46.21mA   -34.14mA   -71.53mA
-535mV    -32.2mA    -20.15mA   -50.06mA
455mV     17.74mA    10.47mA    29.12mA
2.435V    30.47mA    20.58mA    45.4mA
3.6V      83.98mA    58.61mA    126.7mA
[Pullup]
|Voltage   I(typ)   I(min)   I(max)
-1.8V     134mA      85.95mA    224mA
245mV     -10.92mA   -7.399mA   -18.71mA
2.28V     -29.95mA   -22.26mA   -52.02mA
2.445V    -43.86mA   -71.97mA   -63.95mA
2.61V     -75.85mA   -217.6mA   -93.19mA
2.775V    -248.3mA   -409mA     -125.8mA
2.83V     -331.8mA   -477.6mA   -157mA
2.885V    -420.5mA   -547.7mA   -233.5mA
2.94V     -512.7mA   -618.9mA   -341.9mA
2.995V    -607.1mA   -691mA     -465.3mA
3.05V     -703.3mA   -763.9mA   -596.3mA
3.6V      -1.707A    -1.515A    -2.022A
[Ramp]
| variable   typ   min   max
dV/dt_r   0.673/0.567n   0.480/1.004n   0.879/0.256n
dV/dt_f   0.669/0.967n   0.435/1.693n   0.867/0.458n
R_load = 50.000
[Rising Waveform]
R_fixture= 50.000
V_fixture= 0.0
V_fixture_min= 0.0
V_fixture_max= 0.0
|time   V(typ)   V(min)   V(max)
0s        3.523nV    38.23nV    1.999nV
887ps     -48.08uV   1.634uV    -2.853mV
1.088ns   -5.443mV   1.634uV    506.5mV
1.282ns   -22.25mV   122.5uV    1.198V
1.838ns   133.4mV    -2.93mV    1.437V
2.422ns   865mV      -9.226mV   1.459V
3.25ns    1.087V     82.39mV    1.464V
4.329ns   1.113V     624mV      1.465V
5.502ns   1.121V     767.6mV    1.465V
20ns      1.122V     799.4mV    1.465V
[Rising Waveform]
R_fixture= 50.000
V_fixture= 1.800
V_fixture_min= 1.710
V_fixture_max= 1.890
|time   V(typ)   V(min)   V(max)
0s        684.9mV    985.7mV    445.4mV
619ps     684.9mV    985.7mV    452.2mV
803ps     684.8mV    985.7mV    1.199V
1.032ns   676.8mV    985.7mV    1.718V
1.144ns   726.1mV    985.6mV    1.829V
1.354ns   1.328V     985.3mV    1.869V
1.964ns   1.748V     1.024V     1.886V
2.419ns   1.788V     1.573V     1.889V
3.395ns   1.799V     1.688V     1.89V
20ns      1.8V       1.71V      1.89V
[Falling Waveform]
R_fixture= 50.000
V_fixture= 1.800
V_fixture_min= 1.710
V_fixture_max= 1.890
|time   V(typ)   V(min)   V(max)
0s        1.8V       1.71V      1.89V
930ps     1.8V       1.71V      1.901V
1.557ns   1.829V     1.71V      755.4mV
1.856ns   1.772V     1.711V     536.8mV
2.251ns   1.497V     1.728V     472.8mV
3.074ns   918.6mV    1.715V     448.2mV
4.18ns    721.3mV    1.453V     445.5mV
5.405ns   692.9mV    1.152V     445.4mV
6.497ns   686.9mV    1.044V     445.4mV
20ns      684.8mV    985.6mV    445.3mV
[Falling Waveform]
R_fixture= 50.000
V_fixture= 0.0
V_fixture_min= 0.0
V_fixture_max= 0.0
|time   V(typ)   V(min)   V(max)
0s        1.122V     799.4mV    1.465V
668ps     1.122V     799.5mV    1.459V
832ps     1.122V     799.5mV    757.1mV
1.049ns   1.122V     799.5mV    280.1mV
1.253ns   1.077V     799.5mV    50.43mV
1.422ns   578.1mV    799.5mV    19.9mV
2.114ns   46.18mV    807.5mV    2.035mV
2.654ns   8.088mV    189.7mV    461.2uV
3.609ns   1.313mV    18.77mV    80.54uV
20ns      59.11nV    95.61nV    6.244nV
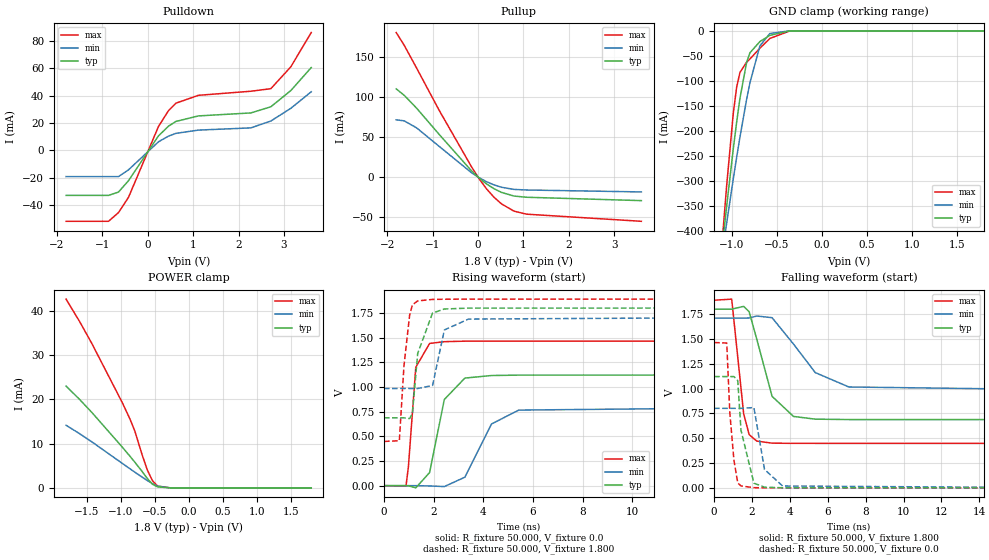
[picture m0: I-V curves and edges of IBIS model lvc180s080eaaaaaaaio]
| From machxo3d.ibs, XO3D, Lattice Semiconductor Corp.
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|   Model lvc180s080eaaaaaaaio
[Model] lvc180s080eaaaaaaaio
Model_type I/O
Polarity   Non-Inverting
Enable   Active-Low
Vinl =  0.630V
Vinh =  1.170V
Vmeas =  0.900V
Cref =  0.0F
Rref =  1.000M
Vref =  0.0V
C_comp   4.200pF   3.800pF   7.500pF
[Temperature Range]   25.000   0.105k   -40.000
[Voltage Range]   1.800V   1.710V   1.890V
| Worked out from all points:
|   slope of the pulldown table from 0 to 0.27 V, typ, clamps not added: 22.7 ohm
|   slope of the pullup table from 0 to 0.27 V, typ, clamps not added: 22.8 ohm
|   GND clamp passes 1 mA (typ) near -0.44 V on its own axis
|   POWER clamp passes 1 mA (typ) near -0.54 V on its own axis
|   rising waveform, R_fixture 50.000, V_fixture 0.0: 20-80 % time 564ps typ, 1.01ns min, 255ps max; typ from 0 V to 1.12 V
|   rising waveform, R_fixture 50.000, V_fixture 1.800: 20-80 % time 364ps typ, 364ps min, 290ps max; typ from 0.688 V to 1.8 V
|   falling waveform, R_fixture 50.000, V_fixture 1.800: 20-80 % time 962ps typ, 1.71ns min, 453ps max; typ from 1.8 V to 0.688 V
|   falling waveform, R_fixture 50.000, V_fixture 0.0: 20-80 % time 380ps typ, 401ps min, 307ps max; typ from 1.12 V to 0 V
[Pulldown]
|Voltage   I(typ)   I(min)   I(max)
-1.8V     -32.67mA   -18.98mA   -51.52mA
-865mV    -32.67mA   -18.98mA   -51.52mA
-645mV    -30.22mA   -18.98mA   -45.17mA
-425mV    -21.97mA   -14.07mA   -34.06mA
235mV     10.62mA    6.321mA    17.45mA
455mV     17.66mA    10.44mA    28.95mA
620mV     21.15mA    12.46mA    34.42mA
1.115V    25.16mA    14.83mA    40.14mA
2.27V     27.33mA    16.45mA    43.11mA
2.71V     31.8mA     21.43mA    44.97mA
3.15V     43.59mA    30.67mA    60.87mA
3.6V      60.34mA    42.73mA    85.8mA
[Pullup]
|Voltage   I(typ)   I(min)   I(max)
-1.8V     110.3mA    71.54mA    180.8mA
-1.625V   102.3mA    70.29mA    165mA
-1.35V    86.09mA    61.46mA    136.3mA
-855mV    53.36mA    38.37mA    83.57mA
-140mV    7.573mA    5.265mA    12.61mA
25mV      -1.264mA   -864.3uA   -2.139mA
190mV     -8.744mA   -5.939mA   -14.93mA
355mV     -14.76mA   -9.939mA   -25.44mA
520mV     -19.33mA   -12.89mA   -33.74mA
795mV     -23.9mA    -15.59mA   -42.8mA
1.07V     -25.4mA    -16.32mA   -46.58mA
3.6V      -29.62mA   -18.74mA   -55.51mA
[GND_clamp]
|Voltage   I(typ)   I(min)   I(max)
-1.8V     -1.677A    -1.372A    -2.207A
-1.097V   -411.6mA   -430.5mA   -392.9mA
-1.06V    -351mA     -384.7mA   -309.8mA
-986mV    -235.9mA   -295.9mA   -164.7mA
-949mV    -183mA     -253.4mA   -113mA
-912mV    -135mA     -212.5mA   -83.33mA
-838mV    -63.16mA   -137.2mA   -62.66mA
-801mV    -43.93mA   -103.8mA   -56.25mA
-690mV    -21.49mA   -30.06mA   -34.72mA
-579mV    -9.043mA   -5.343mA   -15.31mA
-357mV    -110.3uA   -52.32uA   -166.6uA
1.8V      0A         0A         0A
[POWER_clamp]
|Voltage   I(typ)   I(min)   I(max)
-1.8V     22.96mA    14.12mA    42.58mA
-1.604V   19.99mA    12.25mA    37.59mA
-1.419V   16.97mA    10.35mA    32.49mA
-975mV    9.199mA    5.527mA    19.24mA
-864mV    7.174mA    4.324mA    15.6mA
-790mV    5.788mA    3.534mA    12.79mA
-679mV    3.605mA    2.374mA    7.249mA
-605mV    2.066mA    1.631mA    3.958mA
-531mV    820.6uA    942.6uA    1.61mA
-457mV    221.3uA    381uA      405.2uA
-272mV    4.708uA    6.259uA    4.369uA
1.8V      0A         0A         4.229nA
[Ramp]
| variable   typ   min   max
dV/dt_r   0.673/0.562n   0.481/1.003n   0.878/0.253n
dV/dt_f   0.667/0.960n   0.435/1.700n   0.865/0.455n
R_load = 50.000
[Rising Waveform]
R_fixture= 50.000
V_fixture= 0.0
V_fixture_min= 0.0
V_fixture_max= 0.0
|time   V(typ)   V(min)   V(max)
0s        3.652nV    38.62nV    2.158nV
887ps     -46.08uV   1.778uV    -3.193mV
984ps     -923.2uV   1.778uV    190.4mV
1.281ns   -22.3mV    122.7uV    1.2V
1.838ns   133.4mV    -2.933mV   1.441V
2.429ns   873mV      -9.128mV   1.459V
3.257ns   1.09V      85.8mV     1.464V
4.329ns   1.116V     625.3mV    1.464V
5.426ns   1.12V      765.7mV    1.464V
20ns      1.121V     801mV      1.464V
[Rising Waveform]
R_fixture= 50.000
V_fixture= 1.800
V_fixture_min= 1.710
V_fixture_max= 1.890
|time   V(typ)   V(min)   V(max)
0s        687.7mV    984.9mV    448.1mV
619ps     687.7mV    984.9mV    455.1mV
806ps     687.6mV    984.9mV    1.215V
1.033ns   679.5mV    984.9mV    1.726V
1.144ns   729mV      984.7mV    1.832V
1.358ns   1.34V      984.5mV    1.872V
1.956ns   1.749V     1.015V     1.887V
2.431ns   1.79V      1.578V     1.889V
3.405ns   1.799V     1.688V     1.89V
20ns      1.8V       1.71V      1.89V
[Falling Waveform]
R_fixture= 50.000
V_fixture= 1.800
V_fixture_min= 1.710
V_fixture_max= 1.890
|time   V(typ)   V(min)   V(max)
0s        1.8V       1.71V      1.89V
930ps     1.8V       1.71V      1.901V
1.563ns   1.828V     1.71V      745mV
1.851ns   1.774V     1.711V     536.8mV
2.255ns   1.497V     1.731V     471mV
3.062ns   921.8mV    1.714V     450.3mV
4.194ns   719.4mV    1.448V     448.2mV
5.343ns   692mV      1.161V     448.1mV
7.118ns   688mV      1.016V     448.1mV
20ns      687.5mV    984.8mV    448.1mV
[Falling Waveform]
R_fixture= 50.000
V_fixture= 0.0
V_fixture_min= 0.0
V_fixture_max= 0.0
|time   V(typ)   V(min)   V(max)
0s        1.121V     801mV      1.464V
668ps     1.121V     801.1mV    1.459V
832ps     1.121V     801.1mV    754.6mV
1.048ns   1.121V     801mV      278.6mV
1.251ns   1.08V      801mV      49.7mV
1.42ns    581.1mV    801mV      19.1mV
2.103ns   47.2mV     808.8mV    2.097mV
2.663ns   7.12mV     185.6mV    357.1uV
3.616ns   1.001mV    18.75mV    47.95uV
20ns      60.36nV    98.6nV     15.78nV
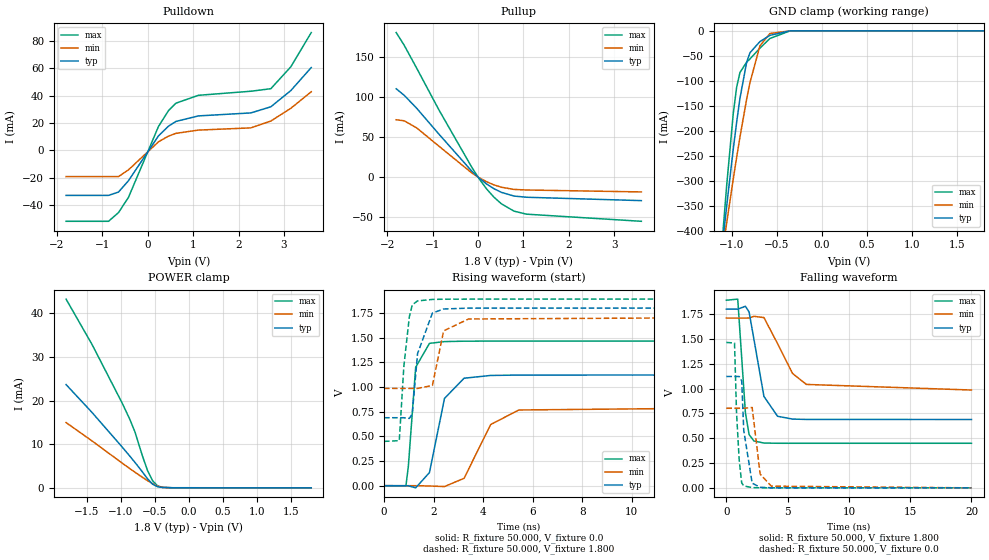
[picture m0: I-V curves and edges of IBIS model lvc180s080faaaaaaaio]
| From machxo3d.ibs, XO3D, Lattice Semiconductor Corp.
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|   Model lvc180s080faaaaaaaio
[Model] lvc180s080faaaaaaaio
Model_type I/O
Polarity   Non-Inverting
Enable   Active-Low
Vinl =  0.630V
Vinh =  1.170V
Vmeas =  0.900V
Cref =  0.0F
Rref =  1.000M
Vref =  0.0V
C_comp   4.200pF   3.800pF   7.500pF
[Temperature Range]   25.000   0.105k   -40.000
[Voltage Range]   1.800V   1.710V   1.890V
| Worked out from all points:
|   slope of the pulldown table from 0 to 0.27 V, typ, clamps not added: 22.7 ohm
|   slope of the pullup table from 0 to 0.27 V, typ, clamps not added: 22.8 ohm
|   GND clamp passes 1 mA (typ) near -0.44 V on its own axis
|   POWER clamp passes 1 mA (typ) near -0.54 V on its own axis
|   rising waveform, R_fixture 50.000, V_fixture 0.0: 20-80 % time 561ps typ, 1.02ns min, 254ps max; typ from 0.001 V to 1.12 V
|   rising waveform, R_fixture 50.000, V_fixture 1.800: 20-80 % time 365ps typ, 362ps min, 288ps max; typ from 0.689 V to 1.8 V
|   falling waveform, R_fixture 50.000, V_fixture 1.800: 20-80 % time 963ps typ, 1.72ns min, 455ps max; typ from 1.8 V to 0.689 V
|   falling waveform, R_fixture 50.000, V_fixture 0.0: 20-80 % time 381ps typ, 403ps min, 308ps max; typ from 1.12 V to 0.001 V
[Pulldown]
|Voltage   I(typ)   I(min)   I(max)
-1.8V     -32.67mA   -18.98mA   -51.52mA
-865mV    -32.67mA   -18.98mA   -51.52mA
-645mV    -30.22mA   -18.98mA   -45.17mA
-425mV    -21.97mA   -14.07mA   -34.06mA
235mV     10.62mA    6.321mA    17.45mA
455mV     17.66mA    10.44mA    28.95mA
620mV     21.15mA    12.46mA    34.42mA
1.115V    25.16mA    14.83mA    40.14mA
2.27V     27.33mA    16.45mA    43.11mA
2.71V     31.79mA    21.43mA    44.95mA
3.15V     43.58mA    30.68mA    60.86mA
3.6V      60.33mA    42.73mA    85.79mA
[Pullup]
|Voltage   I(typ)   I(min)   I(max)
-1.8V     110.4mA    71.62mA    180.8mA
-1.625V   102.3mA    70.34mA    165mA
-1.35V    86.1mA     61.48mA    136.3mA
-855mV    53.36mA    38.38mA    83.56mA
-140mV    7.573mA    5.265mA    12.61mA
25mV      -1.264mA   -864.3uA   -2.139mA
190mV     -8.744mA   -5.939mA   -14.93mA
355mV     -14.76mA   -9.939mA   -25.44mA
520mV     -19.33mA   -12.89mA   -33.74mA
795mV     -23.9mA    -15.59mA   -42.8mA
1.07V     -25.4mA    -16.32mA   -46.58mA
3.6V      -29.62mA   -18.74mA   -55.51mA
[GND_clamp]
|Voltage   I(typ)   I(min)   I(max)
-1.8V     -1.677A    -1.372A    -2.207A
-1.097V   -411.6mA   -430.5mA   -393mA
-1.06V    -351mA     -384.7mA   -309.9mA
-986mV    -235.9mA   -295.9mA   -164.7mA
-949mV    -183mA     -253.4mA   -113mA
-912mV    -135mA     -212.5mA   -83.35mA
-838mV    -63.17mA   -137.2mA   -62.69mA
-801mV    -43.94mA   -103.8mA   -56.28mA
-690mV    -21.51mA   -30.07mA   -34.75mA
-579mV    -9.065mA   -5.356mA   -15.35mA
-357mV    -147.5uA   -72.3uA    -237.1uA
1.8V      -12.41nA   0A         -10.91uA
[POWER_clamp]
|Voltage   I(typ)   I(min)   I(max)
-1.8V     23.65mA    14.95mA    43.22mA
-1.419V   17.27mA    10.75mA    32.84mA
-975mV    9.322mA    5.649mA    19.37mA
-864mV    7.265mA    4.408mA    15.69mA
-790mV    5.86mA     3.598mA    12.87mA
-679mV    3.655mA    2.417mA    7.32mA
-605mV    2.107mA    1.665mA    4.016mA
-531mV    854uA      968.7uA    1.658mA
-457mV    251.6uA    402uA      448.6uA
-383mV    77.17uA    103.3uA    115.3uA
-235mV    19.9uA     13.46uA    32.69uA
1.8V      0A         0A         0A
[Ramp]
| variable   typ   min   max
dV/dt_r   0.673/0.561n   0.481/1.003n   0.878/0.253n
dV/dt_f   0.667/0.963n   0.435/1.693n   0.864/0.456n
R_load = 50.000
[Rising Waveform]
R_fixture= 50.000
V_fixture= 0.0
V_fixture_min= 0.0
V_fixture_max= 0.0
|time   V(typ)   V(min)   V(max)
0s        542.4uV    393.2uV    769.5uV
887ps     445.8uV    419.5uV    -445.5uV
985ps     -400.9uV   394.5uV    196.5mV
1.28ns    -21.38mV   518.1uV    1.2V
1.837ns   133.9mV    -2.453mV   1.442V
2.443ns   884.5mV    -8.199mV   1.46V
3.233ns   1.089V     75.41mV    1.464V
4.306ns   1.117V     619.8mV    1.465V
5.441ns   1.121V     767.3mV    1.465V
20ns      1.122V     801.9mV    1.465V
[Rising Waveform]
R_fixture= 50.000
V_fixture= 1.800
V_fixture_min= 1.710
V_fixture_max= 1.890
|time   V(typ)   V(min)   V(max)
0s        688.8mV    985.7mV    449.4mV
619ps     688.9mV    985.7mV    456.5mV
804ps     688.8mV    985.7mV    1.212V
1.025ns   681.8mV    985.7mV    1.712V
1.143ns   728.6mV    985.6mV    1.832V
1.356ns   1.338V     985.4mV    1.872V
1.956ns   1.749V     1.016V     1.887V
2.409ns   1.79V      1.569V     1.889V
3.417ns   1.799V     1.689V     1.89V
20ns      1.8V       1.71V      1.89V
[Falling Waveform]
R_fixture= 50.000
V_fixture= 1.800
V_fixture_min= 1.710
V_fixture_max= 1.890
|time   V(typ)   V(min)   V(max)
0s        1.8V       1.71V      1.89V
930ps     1.8V       1.71V      1.901V
1.557ns   1.829V     1.71V      755.4mV
1.856ns   1.772V     1.711V     536.8mV
2.251ns   1.497V     1.728V     472.8mV
3.068ns   921.1mV    1.715V     451.8mV
4.18ns    721.3mV    1.453V     449.5mV
5.405ns   692.9mV    1.152V     449.4mV
6.527ns   689.5mV    1.042V     449.4mV
20ns      688.8mV    985.6mV    449.3mV
[Falling Waveform]
R_fixture= 50.000
V_fixture= 0.0
V_fixture_min= 0.0
V_fixture_max= 0.0
|time   V(typ)   V(min)   V(max)
0s        1.122V     801.9mV    1.465V
668ps     1.122V     801.9mV    1.459V
832ps     1.122V     801.9mV    757.1mV
1.049ns   1.122V     801.9mV    280.1mV
1.253ns   1.077V     801.9mV    50.43mV
1.422ns   578.1mV    801.9mV    19.9mV
2.107ns   47.65mV    809.8mV    2.856mV
2.76ns    6.412mV    138.2mV    1.121mV
3.671ns   1.454mV    17.4mV     815.9uV
20ns      542.5uV    393.3uV    769.4uV
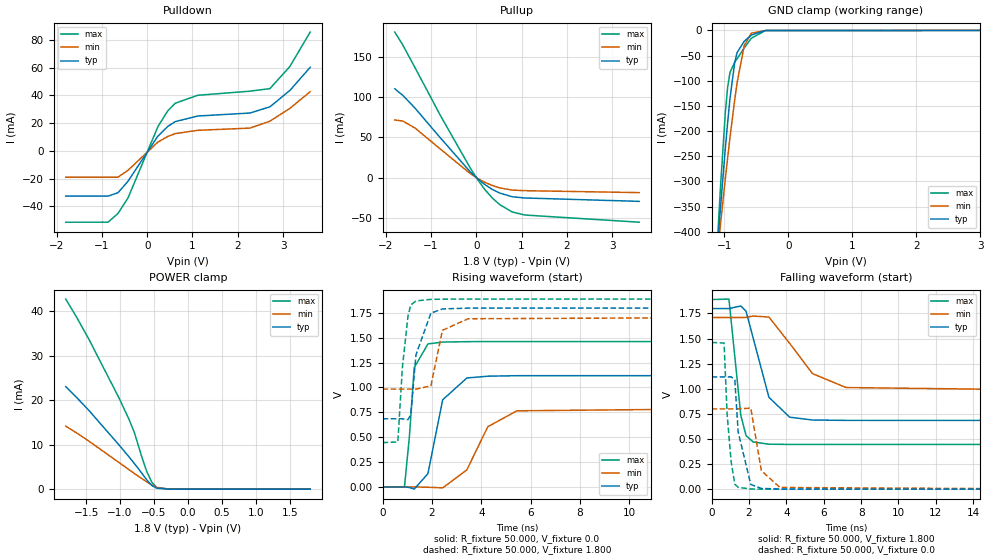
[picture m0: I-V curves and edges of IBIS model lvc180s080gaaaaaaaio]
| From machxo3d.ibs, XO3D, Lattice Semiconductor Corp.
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|   Model lvc180s080gaaaaaaaio
[Model] lvc180s080gaaaaaaaio
Model_type I/O
Polarity   Non-Inverting
Enable   Active-Low
Vinl =  0.630V
Vinh =  1.170V
Vmeas =  0.900V
Cref =  0.0F
Rref =  1.000M
Vref =  0.0V
C_comp   4.200pF   3.800pF   7.500pF
[Temperature Range]   25.000   0.105k   -40.000
[Voltage Range]   1.800V   1.710V   1.890V
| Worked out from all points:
|   slope of the pulldown table from 0 to 0.27 V, typ, clamps not added: 22.7 ohm
|   slope of the pullup table from 0 to 0.27 V, typ, clamps not added: 22.8 ohm
|   GND clamp passes 1 mA (typ) near -0.44 V on its own axis
|   POWER clamp passes 1 mA (typ) near -0.55 V on its own axis
|   rising waveform, R_fixture 50.000, V_fixture 0.0: 20-80 % time 563ps typ, 1.02ns min, 256ps max; typ from 0 V to 1.12 V
|   rising waveform, R_fixture 50.000, V_fixture 1.800: 20-80 % time 369ps typ, 365ps min, 291ps max; typ from 0.685 V to 1.8 V
|   falling waveform, R_fixture 50.000, V_fixture 1.800: 20-80 % time 960ps typ, 1.7ns min, 452ps max; typ from 1.8 V to 0.685 V
|   falling waveform, R_fixture 50.000, V_fixture 0.0: 20-80 % time 372ps typ, 400ps min, 302ps max; typ from 1.12 V to 0 V
[Pulldown]
|Voltage   I(typ)   I(min)   I(max)
-1.8V     -32.67mA   -18.98mA   -51.52mA
-865mV    -32.67mA   -18.98mA   -51.52mA
-645mV    -30.22mA   -18.98mA   -45.17mA
-425mV    -21.97mA   -14.07mA   -34.06mA
235mV     10.62mA    6.321mA    17.45mA
455mV     17.66mA    10.44mA    28.95mA
620mV     21.15mA    12.46mA    34.42mA
1.115V    25.16mA    14.83mA    40.14mA
2.27V     27.33mA    16.45mA    43.11mA
2.71V     31.79mA    21.43mA    44.94mA
3.15V     43.59mA    30.67mA    60.86mA
3.6V      60.34mA    42.73mA    85.79mA
[Pullup]
|Voltage   I(typ)   I(min)   I(max)
-1.8V     110.3mA    71.55mA    180.8mA
-1.625V   102.3mA    70.3mA     165mA
-1.35V    86.1mA     61.46mA    136.3mA
-800mV    49.79mA    35.74mA    77.94mA
-140mV    7.573mA    5.265mA    12.61mA
25mV      -1.264mA   -864.3uA   -2.139mA
190mV     -8.744mA   -5.939mA   -14.93mA
355mV     -14.76mA   -9.939mA   -25.44mA
520mV     -19.33mA   -12.89mA   -33.74mA
795mV     -23.9mA    -15.59mA   -42.8mA
1.07V     -25.4mA    -16.32mA   -46.58mA
3.6V      -29.62mA   -18.74mA   -55.5mA
[GND_clamp]
|Voltage   I(typ)   I(min)   I(max)
-1.8V     -1.677A    -1.372A    -2.207A
-1.097V   -411.7mA   -430.5mA   -393mA
-1.06V    -351mA     -384.7mA   -309.9mA
-986mV    -235.9mA   -295.9mA   -164.8mA
-949mV    -183mA     -253.4mA   -113.1mA
-912mV    -135mA     -212.5mA   -83.39mA
-838mV    -63.2mA    -137.2mA   -62.73mA
-801mV    -43.97mA   -103.8mA   -56.32mA
-690mV    -21.54mA   -30.09mA   -34.79mA
-579mV    -9.102mA   -5.388mA   -15.4mA
-357mV    -191.3uA   -96.81uA   -298.1uA
3.6V      109.7uA    43.11uA    257.2uA
[POWER_clamp]
|Voltage   I(typ)   I(min)   I(max)
-1.8V     23.01mA    14.15mA    42.67mA
-1.641V   20.61mA    12.64mA    38.63mA
-1.456V   17.62mA    10.75mA    33.57mA
-1.012V   9.864mA    5.936mA    20.36mA
-864mV    7.162mA    4.325mA    15.53mA
-790mV    5.771mA    3.533mA    12.74mA
-679mV    3.583mA    2.37mA     7.204mA
-605mV    2.041mA    1.626mA    3.889mA
-531mV    791.7uA    936.7uA    1.526mA
-457mV    198.5uA    375.7uA    334.5uA
-272mV    2.958uA    5.534uA    1.322uA
1.8V      0A         0A         0A
[Ramp]
| variable   typ   min   max
dV/dt_r   0.671/0.563n   0.480/1.004n   0.876/0.254n
dV/dt_f   0.668/0.959n   0.436/1.693n   0.865/0.453n
R_load = 50.000
[Rising Waveform]
R_fixture= 50.000
V_fixture= 0.0
V_fixture_min= 0.0
V_fixture_max= 0.0
|time   V(typ)   V(min)   V(max)
0s        3.523nV    38.23nV    1.999nV
887ps     -48.09uV   1.727uV    -2.853mV
1.088ns   -5.443mV   1.727uV    506.5mV
1.282ns   -22.25mV   123.7uV    1.198V
1.838ns   133.4mV    -2.93mV    1.437V
2.437ns   875.8mV    -8.918mV   1.456V
3.417ns   1.095V     172.1mV    1.46V
4.263ns   1.113V     605.1mV    1.461V
5.447ns   1.118V     765.2mV    1.461V
20ns      1.118V     799.4mV    1.461V
[Rising Waveform]
R_fixture= 50.000
V_fixture= 1.800
V_fixture_min= 1.710
V_fixture_max= 1.890
|time   V(typ)   V(min)   V(max)
0s        684.9mV    983.3mV    445.4mV
619ps     684.9mV    983.3mV    452.2mV
803ps     684.8mV    983.3mV    1.199V
1.032ns   676.8mV    983.3mV    1.718V
1.144ns   726.1mV    983.2mV    1.829V
1.354ns   1.328V     983mV      1.869V
1.958ns   1.746V     1.016V     1.885V
2.426ns   1.789V     1.574V     1.887V
3.465ns   1.797V     1.69V      1.888V
20ns      1.799V     1.709V     1.888V
[Falling Waveform]
R_fixture= 50.000
V_fixture= 1.800
V_fixture_min= 1.710
V_fixture_max= 1.890
|time   V(typ)   V(min)   V(max)
0s        1.799V     1.709V     1.888V
929ps     1.798V     1.709V     1.893V
1.564ns   1.824V     1.709V     735.2mV
1.845ns   1.772V     1.71V      533.4mV
2.222ns   1.507V     1.724V     470.1mV
3.069ns   914.8mV    1.714V     447.7mV
4.177ns   716.9mV    1.452V     445.5mV
5.396ns   688.7mV    1.151V     445.4mV
7.193ns   685mV      1.012V     445.4mV
20ns      684.6mV    983.3mV    445.4mV
[Falling Waveform]
R_fixture= 50.000
V_fixture= 0.0
V_fixture_min= 0.0
V_fixture_max= 0.0
|time   V(typ)   V(min)   V(max)
0s        1.118V     799.4mV    1.461V
668ps     1.118V     799.5mV    1.455V
832ps     1.118V     799.5mV    746.8mV
1.047ns   1.119V     799.5mV    272.5mV
1.244ns   1.088V     799.5mV    50.19mV
1.424ns   567.8mV    799.5mV    18.08mV
2.099ns   46.79mV    807mV      1.859mV
2.663ns   7.496mV    184.2mV    383.1uV
3.655ns   941.3uV    16.95mV    55.46uV
20ns      53.29nV    95.61nV    3.362nV
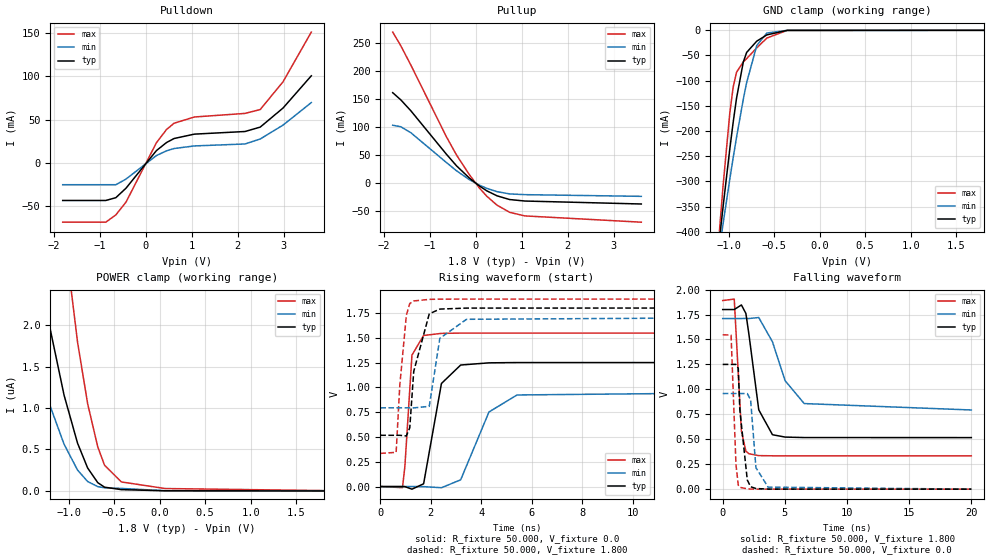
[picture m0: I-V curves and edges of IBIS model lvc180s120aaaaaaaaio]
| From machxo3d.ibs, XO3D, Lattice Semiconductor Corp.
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|   Model lvc180s120aaaaaaaaio
[Model] lvc180s120aaaaaaaaio
Model_type I/O
Polarity   Non-Inverting
Enable   Active-Low
Vinl =  0.630V
Vinh =  1.170V
Vmeas =  0.900V
Cref =  0.0F
Rref =  1.000M
Vref =  0.0V
C_comp   4.200pF   3.800pF   7.500pF
[Temperature Range]   25.000   0.105k   -40.000
[Voltage Range]   1.800V   1.710V   1.890V
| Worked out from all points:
|   slope of the pulldown table from 0 to 0.27 V, typ, clamps not added: 17 ohm
|   slope of the pullup table from 0 to 0.27 V, typ, clamps not added: 18.2 ohm
|   GND clamp passes 1 mA (typ) near -0.44 V on its own axis
|   rising waveform, R_fixture 50.000, V_fixture 0.0: 20-80 % time 494ps typ, 981ps min, 220ps max; typ from 0 V to 1.25 V
|   rising waveform, R_fixture 50.000, V_fixture 1.800: 20-80 % time 364ps typ, 365ps min, 281ps max; typ from 0.517 V to 1.8 V
|   falling waveform, R_fixture 50.000, V_fixture 1.800: 20-80 % time 824ps typ, 1.65ns min, 369ps max; typ from 1.8 V to 0.517 V
|   falling waveform, R_fixture 50.000, V_fixture 0.0: 20-80 % time 375ps typ, 401ps min, 303ps max; typ from 1.25 V to 0 V
[Pulldown]
|Voltage   I(typ)   I(min)   I(max)
-1.8V     -43.56mA   -25.31mA   -68.69mA
-865mV    -43.56mA   -25.31mA   -68.69mA
-645mV    -40.3mA    -25.31mA   -60.23mA
-425mV    -29.3mA    -18.76mA   -45.41mA
235mV     14.17mA    8.428mA    23.27mA
455mV     23.55mA    13.92mA    38.6mA
620mV     28.2mA     16.61mA    45.89mA
1.06V     33.26mA    19.6mA     53.12mA
2.16V     36.3mA     21.87mA    57.24mA
2.49V     41.41mA    27.64mA    61.76mA
2.985V    63.43mA    43.71mA    93.83mA
3.6V      100.8mA    69.77mA    151.4mA
[Pullup]
|Voltage   I(typ)   I(min)   I(max)
-1.8V     161mA      103.1mA    268.8mA
-1.625V   148.3mA    100.4mA    244.6mA
-1.405V   128.7mA    89.74mA    210mA
-635mV    51.69mA    36.83mA    82.78mA
-415mV    30.99mA    22.12mA    50.29mA
-140mV    9.467mA    6.582mA    15.76mA
80mV      -4.903mA   -3.346mA   -8.323mA
245mV     -13.64mA   -9.238mA   -23.35mA
465mV     -22.46mA   -15.03mA   -39.02mA
740mV     -29.1mA    -19.08mA   -51.81mA
1.07V     -31.75mA   -20.4mA    -58.22mA
3.6V      -37.02mA   -23.42mA   -69.39mA
[GND_clamp]
|Voltage   I(typ)   I(min)   I(max)
-1.8V     -1.677A    -1.372A    -2.207A
-1.097V   -411.6mA   -430.5mA   -392.9mA
-1.06V    -351mA     -384.7mA   -309.8mA
-986mV    -235.9mA   -295.9mA   -164.7mA
-949mV    -183mA     -253.4mA   -113mA
-912mV    -135mA     -212.5mA   -83.33mA
-838mV    -63.16mA   -137.2mA   -62.66mA
-801mV    -43.93mA   -103.8mA   -56.25mA
-690mV    -21.49mA   -30.06mA   -34.72mA
-579mV    -9.043mA   -5.343mA   -15.31mA
-357mV    -110.3uA   -52.32uA   -166.6uA
1.8V      0A         0A         0A
[POWER_clamp]
|Voltage   I(typ)   I(min)   I(max)
-1.8V     6.918uA    4.075uA    15.53uA
-1.641V   5.335uA    3.081uA    12.17uA
-1.382V   3.16uA     1.741uA    7.507uA
-1.197V   1.931uA    1.01uA     4.843uA
-1.049V   1.156uA    564.3nA    3.128uA
-901mV    576.3nA    251.8nA    1.796uA
-790mV    276.2nA    113.3nA    1.051uA
-679mV    99.61nA    51.82nA    530.4nA
-605mV    45.4nA     37.93nA    311nA
-420mV    15.43nA    30.13nA    108.3nA
61mV      1.594nA    2.49nA     28.82nA
1.8V      0A         0A         4.229nA
[Ramp]
| variable   typ   min   max
dV/dt_r   0.750/0.490n   0.575/0.977n   0.928/0.217n
dV/dt_f   0.770/0.824n   0.550/1.665n   0.933/0.367n
R_load = 50.000
[Rising Waveform]
R_fixture= 50.000
V_fixture= 0.0
V_fixture_min= 0.0
V_fixture_max= 0.0
|time   V(typ)   V(min)   V(max)
0s        2.942nV    32.1nV     1.699nV
880ps     -81.65uV   23.9uV     -10.92mV
975ps     -901.9uV   -1.059uV   200.6mV
1.256ns   -26.41mV   125.1uV    1.325V
1.718ns   27.48mV    -906.1uV   1.523V
2.425ns   1.039V     -11.82mV   1.544V
3.187ns   1.225V     67.73mV    1.547V
4.309ns   1.247V     751.7mV    1.547V
5.421ns   1.25V      923.2mV    1.547V
20ns      1.25V      958.6mV    1.547V
[Rising Waveform]
R_fixture= 50.000
V_fixture= 1.800
V_fixture_min= 1.710
V_fixture_max= 1.890
|time   V(typ)   V(min)   V(max)
0s        516.8mV    793.5mV    334.2mV
629ps     516.8mV    793.5mV    344.6mV
774ps     516.7mV    793.5mV    1.021V
1.034ns   509.9mV    793.5mV    1.727V
1.169ns   592.6mV    793.3mV    1.845V
1.326ns   1.16V      792.9mV    1.871V
1.942ns   1.741V     808.6mV    1.887V
2.361ns   1.789V     1.494V     1.889V
3.419ns   1.799V     1.686V     1.89V
20ns      1.8V       1.71V      1.89V
[Falling Waveform]
R_fixture= 50.000
V_fixture= 1.800
V_fixture_min= 1.710
V_fixture_max= 1.890
|time   V(typ)   V(min)   V(max)
0s        1.8V       1.71V      1.89V
928ps     1.8V       1.71V      1.905V
1.504ns   1.846V     1.71V      581.6mV
1.864ns   1.761V     1.711V     380.9mV
2.111ns   1.55V      1.71V      355mV
2.899ns   795.1mV    1.72V      336.2mV
4.004ns   545.4mV    1.476V     334.3mV
5.02ns    521.9mV    1.087V     334.2mV
6.556ns   517.2mV    857.8mV    334.2mV
20ns      516.8mV    793.5mV    334.2mV
[Falling Waveform]
R_fixture= 50.000
V_fixture= 0.0
V_fixture_min= 0.0
V_fixture_max= 0.0
|time   V(typ)   V(min)   V(max)
0s        1.25V      958.6mV    1.547V
673ps     1.25V      958.6mV    1.544V
1.066ns   1.25V      958.6mV    247.6mV
1.253ns   1.211V     958.6mV    39.39mV
1.374ns   799.7mV    958.6mV    19.13mV
1.978ns   91.58mV    957.8mV    2.264mV
2.245ns   24.39mV    895.9mV    1.153mV
2.672ns   6.385mV    215.6mV    298.9uV
3.652ns   904.6uV    20.41mV    65.68uV
20ns      46.49nV    185.6nV    11.87nV
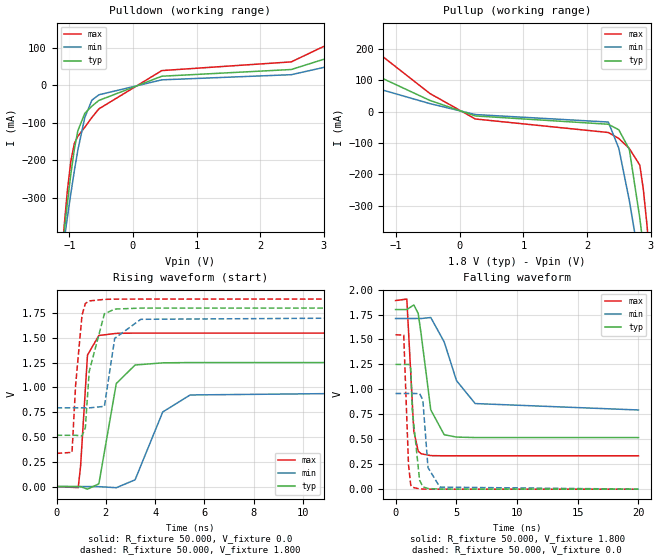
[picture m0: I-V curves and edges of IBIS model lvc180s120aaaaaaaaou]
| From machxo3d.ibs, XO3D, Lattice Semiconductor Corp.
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|   Model lvc180s120aaaaaaaaou
[Model] lvc180s120aaaaaaaaou
Model_type Output
Polarity   Non-Inverting
Enable   Active-High
Vmeas =  0.900V
Cref =  0.0F
Rref =  1.000M
Vref =  0.0V
C_comp   4.200pF   3.800pF   7.500pF
[Temperature Range]   25.000   0.105k   -40.000
[Voltage Range]   1.800V   1.710V   1.890V
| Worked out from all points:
|   slope of the pulldown table from 0 to 0.27 V, typ, clamps not added: 17 ohm
|   slope of the pullup table from 0 to 0.27 V, typ, clamps not added: 18.2 ohm
|   rising waveform, R_fixture 50.000, V_fixture 0.0: 20-80 % time 494ps typ, 981ps min, 220ps max; typ from 0 V to 1.25 V
|   rising waveform, R_fixture 50.000, V_fixture 1.800: 20-80 % time 364ps typ, 365ps min, 281ps max; typ from 0.517 V to 1.8 V
|   falling waveform, R_fixture 50.000, V_fixture 1.800: 20-80 % time 824ps typ, 1.65ns min, 369ps max; typ from 1.8 V to 0.517 V
|   falling waveform, R_fixture 50.000, V_fixture 0.0: 20-80 % time 375ps typ, 401ps min, 303ps max; typ from 1.25 V to 0 V
[Pulldown]
|Voltage   I(typ)   I(min)   I(max)
-1.8V     -1.679A    -1.373A    -2.209A
-1.085V   -400.2mA   -419.6mA   -385.9mA
-1.03V    -314.7mA   -352.9mA   -282.1mA
-975mV    -236.9mA   -288.9mA   -202.8mA
-920mV    -171.4mA   -228.5mA   -155.4mA
-865mV    -121.7mA   -173.2mA   -136.4mA
-755mV    -75.06mA   -86.02mA   -112.2mA
-645mV    -56.23mA   -40.43mA   -86.51mA
-535mV    -41.04mA   -25.93mA   -63.51mA
455mV     23.55mA    13.92mA    38.6mA
2.49V     41.41mA    27.64mA    61.76mA
3.6V      100.8mA    69.77mA    151.4mA
[Pullup]
|Voltage   I(typ)   I(min)   I(max)
-1.8V     161mA      103.1mA    268.9mA
-470mV    35.82mA    25.68mA    57.9mA
245mV     -13.64mA   -9.238mA   -23.35mA
2.335V    -40.04mA   -33.09mA   -66.38mA
2.5V      -57.82mA   -116.8mA   -85.42mA
2.665V    -120mA     -282.7mA   -117.3mA
2.83V     -339mA     -482.1mA   -170.3mA
2.885V    -427.7mA   -552.2mA   -246.8mA
2.94V     -519.9mA   -623.4mA   -355.2mA
2.995V    -614.3mA   -695.6mA   -478.7mA
3.05V     -710.5mA   -768.5mA   -609.8mA
3.6V      -1.714A    -1.52A     -2.036A
[Ramp]
| variable   typ   min   max
dV/dt_r   0.750/0.490n   0.575/0.977n   0.928/0.217n
dV/dt_f   0.770/0.824n   0.550/1.665n   0.933/0.367n
R_load = 50.000
[Rising Waveform]
R_fixture= 50.000
V_fixture= 0.0
V_fixture_min= 0.0
V_fixture_max= 0.0
|time   V(typ)   V(min)   V(max)
0s        2.942nV    32.1nV     1.699nV
880ps     -81.65uV   23.9uV     -10.92mV
975ps     -901.9uV   -1.059uV   200.6mV
1.256ns   -26.41mV   125.1uV    1.325V
1.718ns   27.48mV    -906.1uV   1.523V
2.425ns   1.039V     -11.82mV   1.544V
3.187ns   1.225V     67.73mV    1.547V
4.309ns   1.247V     751.7mV    1.547V
5.421ns   1.25V      923.2mV    1.547V
20ns      1.25V      958.6mV    1.547V
[Rising Waveform]
R_fixture= 50.000
V_fixture= 1.800
V_fixture_min= 1.710
V_fixture_max= 1.890
|time   V(typ)   V(min)   V(max)
0s        516.8mV    793.5mV    334.2mV
629ps     516.8mV    793.5mV    344.6mV
774ps     516.7mV    793.5mV    1.021V
1.034ns   509.9mV    793.5mV    1.727V
1.169ns   592.6mV    793.3mV    1.845V
1.326ns   1.16V      792.9mV    1.871V
1.942ns   1.741V     808.6mV    1.887V
2.361ns   1.789V     1.494V     1.889V
3.419ns   1.799V     1.686V     1.89V
20ns      1.8V       1.71V      1.89V
[Falling Waveform]
R_fixture= 50.000
V_fixture= 1.800
V_fixture_min= 1.710
V_fixture_max= 1.890
|time   V(typ)   V(min)   V(max)
0s        1.8V       1.71V      1.89V
928ps     1.8V       1.71V      1.905V
1.504ns   1.846V     1.71V      581.6mV
1.864ns   1.761V     1.711V     380.9mV
2.111ns   1.55V      1.71V      355mV
2.899ns   795.1mV    1.72V      336.2mV
4.004ns   545.4mV    1.476V     334.3mV
5.02ns    521.9mV    1.087V     334.2mV
6.556ns   517.2mV    857.8mV    334.2mV
20ns      516.8mV    793.5mV    334.2mV
[Falling Waveform]
R_fixture= 50.000
V_fixture= 0.0
V_fixture_min= 0.0
V_fixture_max= 0.0
|time   V(typ)   V(min)   V(max)
0s        1.25V      958.6mV    1.547V
673ps     1.25V      958.6mV    1.544V
1.066ns   1.25V      958.6mV    247.6mV
1.253ns   1.211V     958.6mV    39.39mV
1.374ns   799.7mV    958.6mV    19.13mV
1.978ns   91.58mV    957.8mV    2.264mV
2.245ns   24.39mV    895.9mV    1.153mV
2.672ns   6.385mV    215.6mV    298.9uV
3.652ns   904.6uV    20.41mV    65.68uV
20ns      46.49nV    185.6nV    11.87nV
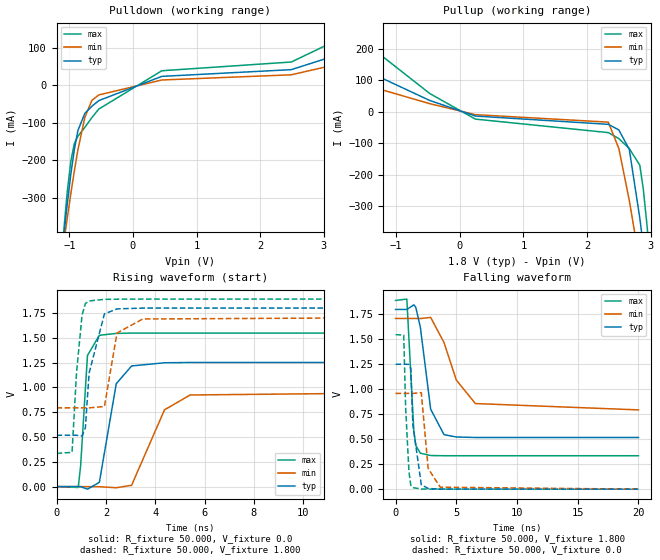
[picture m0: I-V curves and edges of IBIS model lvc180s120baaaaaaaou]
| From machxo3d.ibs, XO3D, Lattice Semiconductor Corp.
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|   Model lvc180s120baaaaaaaou
[Model] lvc180s120baaaaaaaou
Model_type Output
Polarity   Non-Inverting
Enable   Active-High
Vmeas =  0.900V
Cref =  0.0F
Rref =  1.000M
Vref =  0.0V
C_comp   4.200pF   3.800pF   7.500pF
[Temperature Range]   25.000   0.105k   -40.000
[Voltage Range]   1.800V   1.710V   1.890V
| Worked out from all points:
|   slope of the pulldown table from 0 to 0.27 V, typ, clamps not added: 17 ohm
|   slope of the pullup table from 0 to 0.27 V, typ, clamps not added: 18.2 ohm
|   rising waveform, R_fixture 50.000, V_fixture 0.0: 20-80 % time 493ps typ, 973ps min, 219ps max; typ from 0 V to 1.25 V
|   rising waveform, R_fixture 50.000, V_fixture 1.800: 20-80 % time 364ps typ, 364ps min, 282ps max; typ from 0.518 V to 1.8 V
|   falling waveform, R_fixture 50.000, V_fixture 1.800: 20-80 % time 826ps typ, 1.66ns min, 371ps max; typ from 1.8 V to 0.518 V
|   falling waveform, R_fixture 50.000, V_fixture 0.0: 20-80 % time 380ps typ, 400ps min, 303ps max; typ from 1.25 V to 0 V
[Pulldown]
|Voltage   I(typ)   I(min)   I(max)
-1.8V     -1.679A    -1.373A    -2.209A
-1.085V   -400.2mA   -419.6mA   -385.9mA
-1.03V    -314.7mA   -352.9mA   -282.1mA
-975mV    -236.9mA   -288.9mA   -202.9mA
-920mV    -171.4mA   -228.5mA   -155.4mA
-865mV    -121.7mA   -173.2mA   -136.4mA
-755mV    -75.08mA   -86.02mA   -112.3mA
-645mV    -56.25mA   -40.44mA   -86.54mA
-535mV    -41.07mA   -25.94mA   -63.56mA
455mV     23.51mA    13.9mA     38.51mA
2.49V     41.46mA    27.7mA     61.81mA
3.6V      101.5mA    70.75mA    151.9mA
[Pullup]
|Voltage   I(typ)   I(min)   I(max)
-1.8V     161.7mA    103.9mA    269.5mA
-470mV    35.86mA    25.7mA     57.94mA
245mV     -13.65mA   -9.247mA   -23.38mA
2.335V    -40.06mA   -33.09mA   -66.43mA
2.5V      -57.83mA   -116.8mA   -85.45mA
2.665V    -120mA     -282.7mA   -117.3mA
2.83V     -339mA     -482.1mA   -170.3mA
2.885V    -427.7mA   -552.2mA   -246.8mA
2.94V     -519.9mA   -623.4mA   -355.3mA
2.995V    -614.3mA   -695.6mA   -478.7mA
3.05V     -710.5mA   -768.5mA   -609.8mA
3.6V      -1.714A    -1.52A     -2.036A
[Ramp]
| variable   typ   min   max
dV/dt_r   0.750/0.490n   0.575/0.977n   0.928/0.217n
dV/dt_f   0.769/0.826n   0.549/1.665n   0.933/0.369n
R_load = 50.000
[Rising Waveform]
R_fixture= 50.000
V_fixture= 0.0
V_fixture_min= 0.0
V_fixture_max= 0.0
|time   V(typ)   V(min)   V(max)
0s        437uV      326.8uV    605.6uV
880ps     369.6uV    350.8uV    -8.296mV
977ps     -408.4uV   325.8uV    210.7mV
1.254ns   -25.48mV   350.8uV    1.322V
1.736ns   43.8mV     -748.3uV   1.525V
2.42ns    1.037V     -11.12mV   1.544V
3.042ns   1.216V     13.57mV    1.547V
4.375ns   1.248V     774.1mV    1.547V
5.414ns   1.251V     923.6mV    1.547V
20ns      1.251V     959.2mV    1.547V
[Rising Waveform]
R_fixture= 50.000
V_fixture= 1.800
V_fixture_min= 1.710
V_fixture_max= 1.890
|time   V(typ)   V(min)   V(max)
0s        517.6mV    794.2mV    335.1mV
629ps     517.6mV    794.2mV    345.6mV
811ps     517.5mV    794.2mV    1.15V
1.034ns   510.7mV    794.2mV    1.728V
1.169ns   593.5mV    794mV      1.845V
1.32ns    1.144V     793.7mV    1.871V
1.94ns    1.741V     807.6mV    1.887V
2.451ns   1.791V     1.548V     1.889V
3.494ns   1.799V     1.689V     1.89V
20ns      1.8V       1.71V      1.89V
[Falling Waveform]
R_fixture= 50.000
V_fixture= 1.800
V_fixture_min= 1.710
V_fixture_max= 1.890
|time   V(typ)   V(min)   V(max)
0s        1.8V       1.71V      1.89V
929ps     1.8V       1.71V      1.904V
1.504ns   1.846V     1.71V      584.2mV
1.666ns   1.822V     1.71V      438mV
2.04ns    1.623V     1.709V     360.9mV
2.892ns   801mV      1.72V      337.1mV
3.989ns   546.6mV    1.469V     335.2mV
5.002ns   522.7mV    1.093V     335.1mV
6.571ns   517.9mV    857.6mV    335.1mV
20ns      517.5mV    794.2mV    335.1mV
[Falling Waveform]
R_fixture= 50.000
V_fixture= 0.0
V_fixture_min= 0.0
V_fixture_max= 0.0
|time   V(typ)   V(min)   V(max)
0s        1.251V     959.2mV    1.547V
673ps     1.251V     959.3mV    1.544V
832ps     1.251V     959.3mV    814.5mV
1.103ns   1.25V      959.3mV    175.4mV
1.253ns   1.212V     959.3mV    40.55mV
1.426ns   645.2mV    959.2mV    15.92mV
2.119ns   45.82mV    967.1mV    2.125mV
2.685ns   6.775mV    207.9mV    960.6uV
3.678ns   1.344mV    19.95mV    650.7uV
20ns      437.1uV    327uV      605.6uV
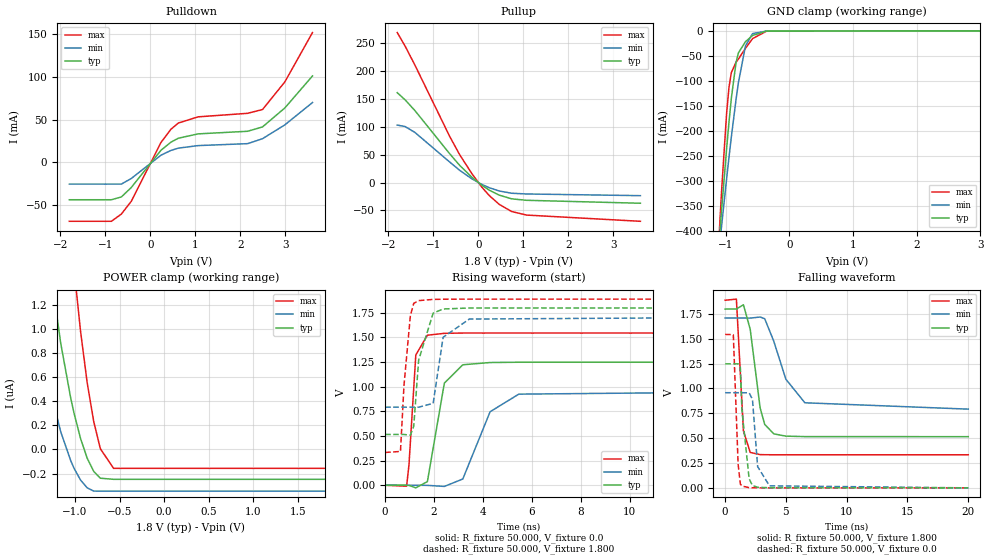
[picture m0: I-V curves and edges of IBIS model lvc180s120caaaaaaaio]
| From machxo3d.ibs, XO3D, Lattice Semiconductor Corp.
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|   Model lvc180s120caaaaaaaio
[Model] lvc180s120caaaaaaaio
Model_type I/O
Polarity   Non-Inverting
Enable   Active-Low
Vinl =  0.630V
Vinh =  1.170V
Vmeas =  0.900V
Cref =  0.0F
Rref =  1.000M
Vref =  0.0V
C_comp   4.200pF   3.800pF   7.500pF
[Temperature Range]   25.000   0.105k   -40.000
[Voltage Range]   1.800V   1.710V   1.890V
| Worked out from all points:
|   slope of the pulldown table from 0 to 0.27 V, typ, clamps not added: 17 ohm
|   slope of the pullup table from 0 to 0.27 V, typ, clamps not added: 18.2 ohm
|   GND clamp passes 1 mA (typ) near -0.44 V on its own axis
|   rising waveform, R_fixture 50.000, V_fixture 0.0: 20-80 % time 494ps typ, 984ps min, 220ps max; typ from 0 V to 1.25 V
|   rising waveform, R_fixture 50.000, V_fixture 1.800: 20-80 % time 369ps typ, 366ps min, 283ps max; typ from 0.515 V to 1.8 V
|   falling waveform, R_fixture 50.000, V_fixture 1.800: 20-80 % time 828ps typ, 1.66ns min, 367ps max; typ from 1.8 V to 0.515 V
|   falling waveform, R_fixture 50.000, V_fixture 0.0: 20-80 % time 372ps typ, 399ps min, 305ps max; typ from 1.25 V to 0 V
[Pulldown]
|Voltage   I(typ)   I(min)   I(max)
-1.8V     -43.56mA   -25.31mA   -68.69mA
-865mV    -43.56mA   -25.31mA   -68.69mA
-645mV    -40.3mA    -25.31mA   -60.23mA
-425mV    -29.3mA    -18.76mA   -45.41mA
235mV     14.17mA    8.428mA    23.27mA
455mV     23.55mA    13.92mA    38.6mA
620mV     28.2mA     16.61mA    45.89mA
1.06V     33.26mA    19.6mA     53.12mA
2.16V     36.29mA    21.86mA    57.24mA
2.49V     41.38mA    27.64mA    61.66mA
2.985V    63.44mA    43.72mA    93.79mA
3.6V      100.8mA    69.8mA     151.4mA
[Pullup]
|Voltage   I(typ)   I(min)   I(max)
-1.8V     161.1mA    103.1mA    268.9mA
-1.625V   148.3mA    100.4mA    244.6mA
-1.405V   128.8mA    89.76mA    210.1mA
-635mV    51.67mA    36.83mA    82.71mA
-415mV    30.97mA    22.11mA    50.15mA
-140mV    9.467mA    6.582mA    15.76mA
80mV      -4.903mA   -3.346mA   -8.323mA
245mV     -13.64mA   -9.238mA   -23.35mA
465mV     -22.46mA   -15.03mA   -39.02mA
740mV     -29.1mA    -19.08mA   -51.81mA
1.07V     -31.75mA   -20.4mA    -58.22mA
3.6V      -37.02mA   -23.42mA   -69.38mA
[GND_clamp]
|Voltage   I(typ)   I(min)   I(max)
-1.8V     -1.677A    -1.372A    -2.207A
-1.097V   -411.7mA   -430.5mA   -393mA
-1.06V    -351mA     -384.7mA   -309.9mA
-986mV    -235.9mA   -295.9mA   -164.8mA
-949mV    -183mA     -253.4mA   -113.1mA
-912mV    -135mA     -212.5mA   -83.39mA
-838mV    -63.2mA    -137.2mA   -62.73mA
-801mV    -43.97mA   -103.8mA   -56.32mA
-690mV    -21.54mA   -30.09mA   -34.79mA
-579mV    -9.102mA   -5.388mA   -15.4mA
-357mV    -191.3uA   -96.81uA   -298.1uA
3.6V      109.7uA    43.11uA    257.2uA
[POWER_clamp]
|Voltage   I(typ)   I(min)   I(max)
-1.8V     5.719uA    2.929uA    14.07uA
-1.567V   3.495uA    1.631uA    8.906uA
-1.308V   1.654uA    574.5nA    4.658uA
-1.16V    879.1nA    145.5nA    2.867uA
-1.049V   428.7nA    -92.06nA   1.807uA
-1.012V   303.4nA    -154.8nA   1.506uA
-938mV    90.16nA    -254.6nA   980.1nA
-864mV    -72.34nA   -318.6nA   555.1nA
-790mV    -182.4nA   -345.7nA   230.3nA
-716mV    -238.9nA   -346.3nA   6.02nA
-568mV    -248.1nA   -346.3nA   -157.2nA
1.8V      -248.1nA   -346.3nA   -157.2nA
[Ramp]
| variable   typ   min   max
dV/dt_r   0.749/0.492n   0.574/0.975n   0.927/0.218n
dV/dt_f   0.770/0.822n   0.550/1.672n   0.933/0.367n
R_load = 50.000
[Rising Waveform]
R_fixture= 50.000
V_fixture= 0.0
V_fixture_min= 0.0
V_fixture_max= 0.0
|time   V(typ)   V(min)   V(max)
0s        2.84nV     31.79nV    1.575nV
881ps     -70.89uV   23.86uV    -9.625mV
977ps     -843uV     -1.091uV   208mV
1.256ns   -26.36mV   124.9uV    1.321V
1.73ns    37.17mV    -1.094mV   1.522V
2.424ns   1.036V     -11.75mV   1.541V
3.178ns   1.222V     63.3mV     1.544V
4.296ns   1.245V     745.9mV    1.544V
5.47ns    1.248V     924.3mV    1.544V
20ns      1.248V     957.3mV    1.544V
[Rising Waveform]
R_fixture= 50.000
V_fixture= 1.800
V_fixture_min= 1.710
V_fixture_max= 1.890
|time   V(typ)   V(min)   V(max)
0s        515.2mV    792.2mV    332.7mV
629ps     515.2mV    792.2mV    342.9mV
774ps     515mV      792.2mV    1.016V
1.034ns   508.3mV    792.2mV    1.722V
1.172ns   598mV      792mV      1.845V
1.372ns   1.269V     791.7mV    1.873V
1.966ns   1.746V     831.2mV    1.885V
2.373ns   1.788V     1.501V     1.887V
3.447ns   1.798V     1.686V     1.888V
20ns      1.799V     1.709V     1.888V
[Falling Waveform]
R_fixture= 50.000
V_fixture= 1.800
V_fixture_min= 1.710
V_fixture_max= 1.890
|time   V(typ)   V(min)   V(max)
0s        1.799V     1.709V     1.888V
925ps     1.799V     1.709V     1.899V
1.505ns   1.842V     1.709V     573.1mV
2.063ns   1.595V     1.708V     356.4mV
2.877ns   804.8mV    1.719V     334.7mV
3.254ns   638.9mV    1.702V     333.6mV
3.999ns   543.6mV    1.476V     332.8mV
4.994ns   520.3mV    1.093V     332.8mV
6.56ns    515.7mV    856mV      332.7mV
20ns      515.2mV    792.2mV    332.7mV
[Falling Waveform]
R_fixture= 50.000
V_fixture= 0.0
V_fixture_min= 0.0
V_fixture_max= 0.0
|time   V(typ)   V(min)   V(max)
0s        1.248V     957.3mV    1.544V
673ps     1.248V     957.4mV    1.541V
1.066ns   1.248V     957.3mV    240.1mV
1.25ns    1.214V     957.3mV    38.76mV
1.376ns   789.6mV    957.3mV    18.48mV
1.973ns   91.57mV    956.4mV    2.261mV
2.249ns   23.43mV    888.7mV    1.149mV
2.672ns   6.322mV    214.2mV    291uV
3.645ns   904.5uV    20.49mV    58.05uV
20ns      43.79nV    181.7nV    2.491nV
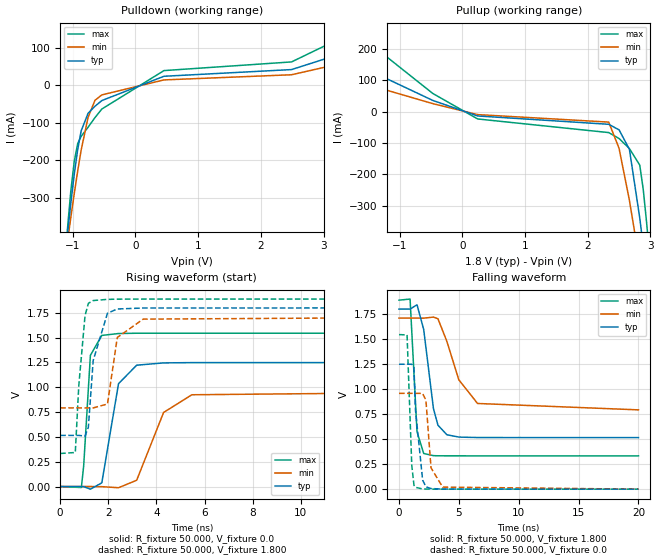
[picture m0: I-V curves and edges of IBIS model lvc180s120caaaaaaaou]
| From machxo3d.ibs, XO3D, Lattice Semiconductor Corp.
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|   Model lvc180s120caaaaaaaou
[Model] lvc180s120caaaaaaaou
Model_type Output
Polarity   Non-Inverting
Enable   Active-High
Vmeas =  0.900V
Cref =  0.0F
Rref =  1.000M
Vref =  0.0V
C_comp   4.200pF   3.800pF   7.500pF
[Temperature Range]   25.000   0.105k   -40.000
[Voltage Range]   1.800V   1.710V   1.890V
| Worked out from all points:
|   slope of the pulldown table from 0 to 0.27 V, typ, clamps not added: 16.9 ohm
|   slope of the pullup table from 0 to 0.27 V, typ, clamps not added: 18.2 ohm
|   rising waveform, R_fixture 50.000, V_fixture 0.0: 20-80 % time 494ps typ, 984ps min, 220ps max; typ from 0 V to 1.25 V
|   rising waveform, R_fixture 50.000, V_fixture 1.800: 20-80 % time 369ps typ, 366ps min, 283ps max; typ from 0.515 V to 1.8 V
|   falling waveform, R_fixture 50.000, V_fixture 1.800: 20-80 % time 828ps typ, 1.66ns min, 367ps max; typ from 1.8 V to 0.515 V
|   falling waveform, R_fixture 50.000, V_fixture 0.0: 20-80 % time 372ps typ, 399ps min, 305ps max; typ from 1.25 V to 0 V
[Pulldown]
|Voltage   I(typ)   I(min)   I(max)
-1.8V     -1.679A    -1.373A    -2.209A
-1.085V   -400.2mA   -419.6mA   -385.9mA
-1.03V    -314.7mA   -352.9mA   -282.2mA
-975mV    -236.9mA   -288.9mA   -202.9mA
-920mV    -171.5mA   -228.5mA   -155.5mA
-865mV    -121.8mA   -173.2mA   -136.5mA
-755mV    -75.11mA   -86.04mA   -112.3mA
-645mV    -56.28mA   -40.47mA   -86.59mA
-535mV    -41.11mA   -25.98mA   -63.61mA
455mV     23.63mA    13.95mA    38.77mA
2.49V     41.48mA    27.68mA    61.9mA
3.6V      100.9mA    69.85mA    151.7mA
[Pullup]
|Voltage   I(typ)   I(min)   I(max)
-1.8V     161.2mA    103.1mA    269.2mA
-470mV    35.91mA    25.71mA    58.07mA
245mV     -13.54mA   -9.201mA   -23.11mA
2.335V    -40.1mA    -33.12mA   -66.49mA
2.5V      -57.85mA   -116.8mA   -85.48mA
2.665V    -120mA     -282.7mA   -117.4mA
2.83V     -339mA     -482.1mA   -170.3mA
2.885V    -427.7mA   -552.2mA   -246.8mA
2.94V     -519.9mA   -623.4mA   -355.3mA
2.995V    -614.4mA   -695.6mA   -478.7mA
3.05V     -710.5mA   -768.5mA   -609.8mA
3.6V      -1.714A    -1.52A     -2.036A
[Ramp]
| variable   typ   min   max
dV/dt_r   0.749/0.492n   0.574/0.975n   0.927/0.218n
dV/dt_f   0.770/0.822n   0.550/1.672n   0.933/0.367n
R_load = 50.000
[Rising Waveform]
R_fixture= 50.000
V_fixture= 0.0
V_fixture_min= 0.0
V_fixture_max= 0.0
|time   V(typ)   V(min)   V(max)
0s        2.84nV     31.79nV    1.575nV
881ps     -70.89uV   23.86uV    -9.625mV
977ps     -843uV     -1.091uV   208mV
1.256ns   -26.36mV   124.9uV    1.321V
1.73ns    37.17mV    -1.094mV   1.522V
2.424ns   1.036V     -11.75mV   1.541V
3.178ns   1.222V     63.3mV     1.544V
4.296ns   1.245V     745.9mV    1.544V
5.47ns    1.248V     924.3mV    1.544V
20ns      1.248V     957.3mV    1.544V
[Rising Waveform]
R_fixture= 50.000
V_fixture= 1.800
V_fixture_min= 1.710
V_fixture_max= 1.890
|time   V(typ)   V(min)   V(max)
0s        515.2mV    792.2mV    332.7mV
629ps     515.2mV    792.2mV    342.9mV
774ps     515mV      792.2mV    1.016V
1.034ns   508.3mV    792.2mV    1.722V
1.172ns   598mV      792mV      1.845V
1.372ns   1.269V     791.7mV    1.873V
1.966ns   1.746V     831.2mV    1.885V
2.373ns   1.788V     1.501V     1.887V
3.447ns   1.798V     1.686V     1.888V
20ns      1.799V     1.709V     1.888V
[Falling Waveform]
R_fixture= 50.000
V_fixture= 1.800
V_fixture_min= 1.710
V_fixture_max= 1.890
|time   V(typ)   V(min)   V(max)
0s        1.799V     1.709V     1.888V
925ps     1.799V     1.709V     1.899V
1.505ns   1.842V     1.709V     573.1mV
2.063ns   1.595V     1.708V     356.4mV
2.877ns   804.8mV    1.719V     334.7mV
3.254ns   638.9mV    1.702V     333.6mV
3.999ns   543.6mV    1.476V     332.8mV
4.994ns   520.3mV    1.093V     332.8mV
6.56ns    515.7mV    856mV      332.7mV
20ns      515.2mV    792.2mV    332.7mV
[Falling Waveform]
R_fixture= 50.000
V_fixture= 0.0
V_fixture_min= 0.0
V_fixture_max= 0.0
|time   V(typ)   V(min)   V(max)
0s        1.248V     957.3mV    1.544V
673ps     1.248V     957.4mV    1.541V
1.066ns   1.248V     957.3mV    240.1mV
1.25ns    1.214V     957.3mV    38.76mV
1.376ns   789.6mV    957.3mV    18.48mV
1.973ns   91.57mV    956.4mV    2.261mV
2.249ns   23.43mV    888.7mV    1.149mV
2.672ns   6.322mV    214.2mV    291uV
3.645ns   904.5uV    20.49mV    58.05uV
20ns      43.79nV    181.7nV    2.491nV
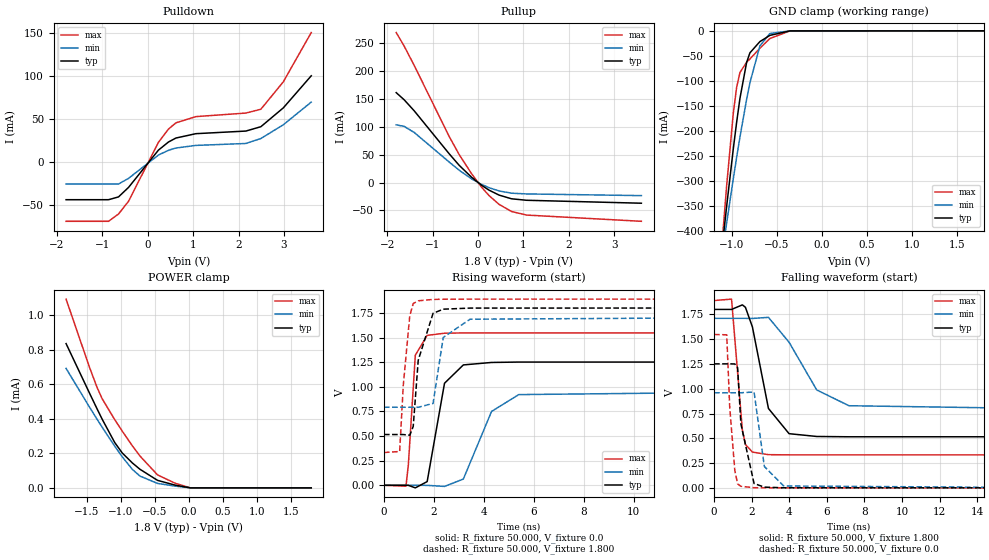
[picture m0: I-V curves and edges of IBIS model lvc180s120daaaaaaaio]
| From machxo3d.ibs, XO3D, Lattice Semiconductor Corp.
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|   Model lvc180s120daaaaaaaio
[Model] lvc180s120daaaaaaaio
Model_type I/O
Polarity   Non-Inverting
Enable   Active-Low
Vinl =  0.630V
Vinh =  1.170V
Vmeas =  0.900V
Cref =  0.0F
Rref =  1.000M
Vref =  0.0V
C_comp   4.200pF   3.800pF   7.500pF
[Temperature Range]   25.000   0.105k   -40.000
[Voltage Range]   1.800V   1.710V   1.890V
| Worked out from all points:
|   slope of the pulldown table from 0 to 0.27 V, typ, clamps not added: 17 ohm
|   slope of the pullup table from 0 to 0.27 V, typ, clamps not added: 18.2 ohm
|   GND clamp passes 1 mA (typ) near -0.44 V on its own axis
|   rising waveform, R_fixture 50.000, V_fixture 0.0: 20-80 % time 496ps typ, 987ps min, 221ps max; typ from 0 V to 1.25 V
|   rising waveform, R_fixture 50.000, V_fixture 1.800: 20-80 % time 371ps typ, 367ps min, 282ps max; typ from 0.515 V to 1.8 V
|   falling waveform, R_fixture 50.000, V_fixture 1.800: 20-80 % time 830ps typ, 1.67ns min, 372ps max; typ from 1.8 V to 0.515 V
|   falling waveform, R_fixture 50.000, V_fixture 0.0: 20-80 % time 379ps typ, 402ps min, 303ps max; typ from 1.25 V to 0 V
[Pulldown]
|Voltage   I(typ)   I(min)   I(max)
-1.8V     -43.56mA   -25.31mA   -68.69mA
-865mV    -43.56mA   -25.31mA   -68.69mA
-645mV    -40.3mA    -25.31mA   -60.23mA
-425mV    -29.3mA    -18.76mA   -45.41mA
235mV     14.17mA    8.428mA    23.27mA
455mV     23.55mA    13.92mA    38.6mA
620mV     28.2mA     16.61mA    45.89mA
1.06V     33.26mA    19.6mA     53.12mA
2.16V     36.3mA     21.87mA    57.24mA
2.49V     41.36mA    27.61mA    61.68mA
2.985V    63.29mA    43.64mA    93.61mA
3.6V      100.6mA    70mA       150.9mA
[Pullup]
|Voltage   I(typ)   I(min)   I(max)
-1.8V     160.9mA    103.3mA    268.4mA
-1.625V   148.1mA    100.5mA    244.2mA
-1.405V   128.5mA    89.72mA    209.8mA
-635mV    51.65mA    36.82mA    82.7mA
-415mV    30.98mA    22.12mA    50.28mA
-140mV    9.467mA    6.582mA    15.76mA
80mV      -4.903mA   -3.346mA   -8.323mA
245mV     -13.64mA   -9.238mA   -23.35mA
465mV     -22.46mA   -15.03mA   -39.02mA
740mV     -29.1mA    -19.08mA   -51.81mA
1.07V     -31.75mA   -20.4mA    -58.22mA
3.6V      -37.02mA   -23.42mA   -69.38mA
[GND_clamp]
|Voltage   I(typ)   I(min)   I(max)
-1.8V     -1.677A    -1.372A    -2.207A
-1.097V   -411.7mA   -430.5mA   -393mA
-1.06V    -351mA     -384.7mA   -309.9mA
-986mV    -235.9mA   -295.9mA   -164.8mA
-949mV    -183mA     -253.4mA   -113.1mA
-912mV    -135mA     -212.5mA   -83.39mA
-838mV    -63.2mA    -137.2mA   -62.73mA
-801mV    -43.97mA   -103.8mA   -56.32mA
-690mV    -21.54mA   -30.09mA   -34.79mA
-579mV    -9.102mA   -5.388mA   -15.4mA
-357mV    -191.3uA   -96.81uA   -298.1uA
1.8V      -12.41nA   0A         -10.91uA
[POWER_clamp]
|Voltage   I(typ)   I(min)   I(max)
-1.8V     836.1uA    692.5uA    1.094mA
-1.456V   549uA      467.8uA    698.7uA
-1.345V   458uA      397.8uA    582.4uA
-1.271V   398.7uA    352uA      517.3uA
-1.086V   262.9uA    241.7uA    395.6uA
-975mV    202uA      179.8uA    328.7uA
-827mV    144.5uA    107.4uA    243.8uA
-716mV    108uA      68.49uA    184.9uA
-457mV    43.42uA    25.76uA    75.17uA
-198mV    15.77uA    10.09uA    26.67uA
24mV      0A         0A         0A
1.8V      0A         0A         0A
[Ramp]
| variable   typ   min   max
dV/dt_r   0.751/0.494n   0.576/0.978n   0.928/0.218n
dV/dt_f   0.771/0.824n   0.551/1.682n   0.934/0.369n
R_load = 50.000
[Rising Waveform]
R_fixture= 50.000
V_fixture= 0.0
V_fixture_min= 0.0
V_fixture_max= 0.0
|time   V(typ)   V(min)   V(max)
0s        2.84nV     31.79nV    1.575nV
881ps     -70.9uV    23.83uV    -9.625mV
977ps     -843uV     -1.095uV   208mV
1.256ns   -26.36mV   124.9uV    1.321V
1.73ns    37.17mV    -1.094mV   1.522V
2.424ns   1.036V     -11.78mV   1.544V
3.178ns   1.222V     63.3mV     1.547V
4.307ns   1.247V     749.7mV    1.547V
5.397ns   1.251V     920.6mV    1.547V
20ns      1.251V     959.2mV    1.547V
[Rising Waveform]
R_fixture= 50.000
V_fixture= 1.800
V_fixture_min= 1.710
V_fixture_max= 1.890
|time   V(typ)   V(min)   V(max)
0s        515.2mV    792.2mV    332.7mV
629ps     515.2mV    792.2mV    342.9mV
774ps     515mV      792.2mV    1.016V
1.034ns   508.3mV    792.2mV    1.722V
1.172ns   598mV      791.9mV    1.845V
1.372ns   1.269V     791.7mV    1.873V
1.966ns   1.746V     831.2mV    1.887V
2.373ns   1.788V     1.501V     1.889V
3.447ns   1.799V     1.686V     1.89V
20ns      1.8V       1.71V      1.89V
[Falling Waveform]
R_fixture= 50.000
V_fixture= 1.800
V_fixture_min= 1.710
V_fixture_max= 1.890
|time   V(typ)   V(min)   V(max)
0s        1.8V       1.71V      1.89V
929ps     1.8V       1.71V      1.904V
1.504ns   1.846V     1.71V      584.2mV
1.666ns   1.822V     1.71V      438mV
2.04ns    1.623V     1.709V     360.9mV
2.892ns   801mV      1.72V      334.9mV
3.989ns   546.6mV    1.469V     332.9mV
5.461ns   518.4mV    987.7mV    332.7mV
7.172ns   515.3mV    828.6mV    332.7mV
20ns      515.2mV    792.4mV    332.7mV
[Falling Waveform]
R_fixture= 50.000
V_fixture= 0.0
V_fixture_min= 0.0
V_fixture_max= 0.0
|time   V(typ)   V(min)   V(max)
0s        1.251V     959.2mV    1.547V
673ps     1.251V     959.3mV    1.544V
832ps     1.251V     959.3mV    814.5mV
1.103ns   1.25V      959.3mV    175.4mV
1.253ns   1.212V     959.3mV    40.55mV
1.426ns   645.2mV    959.2mV    15.92mV
2.127ns   44mV       967mV      1.566mV
2.673ns   7.358mV    216mV      376.8uV
3.7ns     996.8uV    18.96mV    50.99uV
20ns      42.68nV    181.6nV    7.702nV
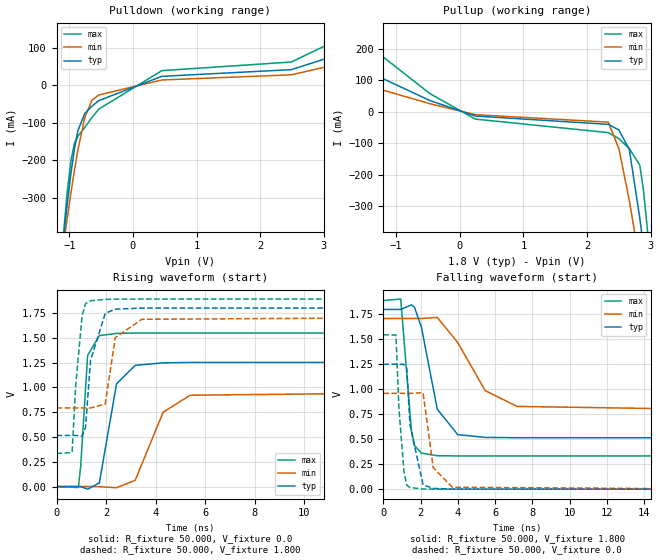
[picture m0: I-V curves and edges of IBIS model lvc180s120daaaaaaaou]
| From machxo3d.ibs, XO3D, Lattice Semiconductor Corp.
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|   Model lvc180s120daaaaaaaou
[Model] lvc180s120daaaaaaaou
Model_type Output
Polarity   Non-Inverting
Enable   Active-High
Vmeas =  0.900V
Cref =  0.0F
Rref =  1.000M
Vref =  0.0V
C_comp   4.200pF   3.800pF   7.500pF
[Temperature Range]   25.000   0.105k   -40.000
[Voltage Range]   1.800V   1.710V   1.890V
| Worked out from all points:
|   slope of the pulldown table from 0 to 0.27 V, typ, clamps not added: 16.9 ohm
|   slope of the pullup table from 0 to 0.27 V, typ, clamps not added: 18.2 ohm
|   rising waveform, R_fixture 50.000, V_fixture 0.0: 20-80 % time 496ps typ, 987ps min, 221ps max; typ from 0 V to 1.25 V
|   rising waveform, R_fixture 50.000, V_fixture 1.800: 20-80 % time 371ps typ, 367ps min, 282ps max; typ from 0.515 V to 1.8 V
|   falling waveform, R_fixture 50.000, V_fixture 1.800: 20-80 % time 830ps typ, 1.67ns min, 372ps max; typ from 1.8 V to 0.515 V
|   falling waveform, R_fixture 50.000, V_fixture 0.0: 20-80 % time 379ps typ, 402ps min, 303ps max; typ from 1.25 V to 0 V
[Pulldown]
|Voltage   I(typ)   I(min)   I(max)
-1.8V     -1.679A    -1.373A    -2.209A
-1.085V   -400.2mA   -419.6mA   -385.9mA
-1.03V    -314.7mA   -352.9mA   -282.2mA
-975mV    -236.9mA   -288.9mA   -202.9mA
-920mV    -171.5mA   -228.5mA   -155.5mA
-865mV    -121.8mA   -173.2mA   -136.5mA
-755mV    -75.11mA   -86.04mA   -112.3mA
-645mV    -56.28mA   -40.47mA   -86.59mA
-535mV    -41.11mA   -25.98mA   -63.61mA
455mV     23.63mA    13.95mA    38.77mA
2.49V     41.46mA    27.7mA     61.81mA
3.6V      101.5mA    70.75mA    151.9mA
[Pullup]
|Voltage   I(typ)   I(min)   I(max)
-1.8V     161.7mA    103.9mA    269.5mA
-470mV    35.86mA    25.7mA     57.94mA
245mV     -13.65mA   -9.247mA   -23.38mA
2.335V    -40.1mA    -33.12mA   -66.49mA
2.5V      -57.85mA   -116.8mA   -85.48mA
2.665V    -120mA     -282.7mA   -117.4mA
2.83V     -339mA     -482.1mA   -170.3mA
2.885V    -427.7mA   -552.2mA   -246.8mA
2.94V     -519.9mA   -623.4mA   -355.3mA
2.995V    -614.4mA   -695.6mA   -478.7mA
3.05V     -710.5mA   -768.5mA   -609.8mA
3.6V      -1.714A    -1.52A     -2.036A
[Ramp]
| variable   typ   min   max
dV/dt_r   0.751/0.494n   0.576/0.978n   0.928/0.218n
dV/dt_f   0.771/0.824n   0.551/1.682n   0.934/0.369n
R_load = 50.000
[Rising Waveform]
R_fixture= 50.000
V_fixture= 0.0
V_fixture_min= 0.0
V_fixture_max= 0.0
|time   V(typ)   V(min)   V(max)
0s        2.84nV     31.79nV    1.575nV
881ps     -70.9uV    23.83uV    -9.625mV
977ps     -843uV     -1.095uV   208mV
1.256ns   -26.36mV   124.9uV    1.321V
1.73ns    37.17mV    -1.094mV   1.522V
2.424ns   1.036V     -11.78mV   1.544V
3.178ns   1.222V     63.3mV     1.547V
4.307ns   1.247V     749.7mV    1.547V
5.397ns   1.251V     920.6mV    1.547V
20ns      1.251V     959.2mV    1.547V
[Rising Waveform]
R_fixture= 50.000
V_fixture= 1.800
V_fixture_min= 1.710
V_fixture_max= 1.890
|time   V(typ)   V(min)   V(max)
0s        515.2mV    792.2mV    332.7mV
629ps     515.2mV    792.2mV    342.9mV
774ps     515mV      792.2mV    1.016V
1.034ns   508.3mV    792.2mV    1.722V
1.172ns   598mV      791.9mV    1.845V
1.372ns   1.269V     791.7mV    1.873V
1.966ns   1.746V     831.2mV    1.887V
2.373ns   1.788V     1.501V     1.889V
3.447ns   1.799V     1.686V     1.89V
20ns      1.8V       1.71V      1.89V
[Falling Waveform]
R_fixture= 50.000
V_fixture= 1.800
V_fixture_min= 1.710
V_fixture_max= 1.890
|time   V(typ)   V(min)   V(max)
0s        1.8V       1.71V      1.89V
929ps     1.8V       1.71V      1.904V
1.504ns   1.846V     1.71V      584.2mV
1.666ns   1.822V     1.71V      438mV
2.04ns    1.623V     1.709V     360.9mV
2.892ns   801mV      1.72V      334.9mV
3.989ns   546.6mV    1.469V     332.9mV
5.461ns   518.4mV    987.7mV    332.7mV
7.172ns   515.3mV    828.6mV    332.7mV
20ns      515.2mV    792.4mV    332.7mV
[Falling Waveform]
R_fixture= 50.000
V_fixture= 0.0
V_fixture_min= 0.0
V_fixture_max= 0.0
|time   V(typ)   V(min)   V(max)
0s        1.251V     959.2mV    1.547V
673ps     1.251V     959.3mV    1.544V
832ps     1.251V     959.3mV    814.5mV
1.103ns   1.25V      959.3mV    175.4mV
1.253ns   1.212V     959.3mV    40.55mV
1.426ns   645.2mV    959.2mV    15.92mV
2.127ns   44mV       967mV      1.566mV
2.673ns   7.358mV    216mV      376.8uV
3.7ns     996.8uV    18.96mV    50.99uV
20ns      42.68nV    181.6nV    7.702nV
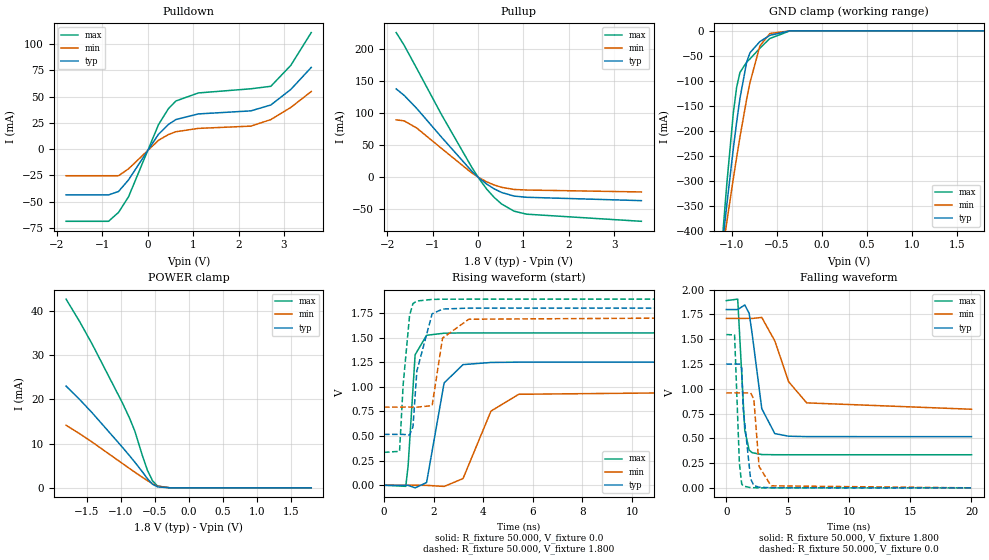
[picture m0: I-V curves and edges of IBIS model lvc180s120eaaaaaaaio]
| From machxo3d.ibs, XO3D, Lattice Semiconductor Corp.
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|   Model lvc180s120eaaaaaaaio
[Model] lvc180s120eaaaaaaaio
Model_type I/O
Polarity   Non-Inverting
Enable   Active-Low
Vinl =  0.630V
Vinh =  1.170V
Vmeas =  0.900V
Cref =  0.0F
Rref =  1.000M
Vref =  0.0V
C_comp   4.200pF   3.800pF   7.500pF
[Temperature Range]   25.000   0.105k   -40.000
[Voltage Range]   1.800V   1.710V   1.890V
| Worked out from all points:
|   slope of the pulldown table from 0 to 0.27 V, typ, clamps not added: 17 ohm
|   slope of the pullup table from 0 to 0.27 V, typ, clamps not added: 18.2 ohm
|   GND clamp passes 1 mA (typ) near -0.44 V on its own axis
|   POWER clamp passes 1 mA (typ) near -0.54 V on its own axis
|   rising waveform, R_fixture 50.000, V_fixture 0.0: 20-80 % time 494ps typ, 983ps min, 220ps max; typ from 0 V to 1.25 V
|   rising waveform, R_fixture 50.000, V_fixture 1.800: 20-80 % time 364ps typ, 365ps min, 281ps max; typ from 0.517 V to 1.8 V
|   falling waveform, R_fixture 50.000, V_fixture 1.800: 20-80 % time 824ps typ, 1.65ns min, 369ps max; typ from 1.8 V to 0.517 V
|   falling waveform, R_fixture 50.000, V_fixture 0.0: 20-80 % time 375ps typ, 401ps min, 303ps max; typ from 1.25 V to 0 V
[Pulldown]
|Voltage   I(typ)   I(min)   I(max)
-1.8V     -43.56mA   -25.31mA   -68.69mA
-865mV    -43.56mA   -25.31mA   -68.69mA
-645mV    -40.3mA    -25.31mA   -60.23mA
-425mV    -29.3mA    -18.76mA   -45.41mA
235mV     14.17mA    8.428mA    23.27mA
455mV     23.55mA    13.92mA    38.6mA
620mV     28.2mA     16.61mA    45.89mA
1.115V    33.55mA    19.77mA    53.52mA
2.27V     36.44mA    21.92mA    57.47mA
2.71V     42.06mA    28.16mA    59.85mA
3.15V     56.83mA    39.74mA    79.78mA
3.6V      77.82mA    54.86mA    111mA
[Pullup]
|Voltage   I(typ)   I(min)   I(max)
-1.8V     138mA      89.54mA    226.3mA
-1.625V   127.9mA    87.94mA    206.4mA
-1.35V    107.6mA    76.85mA    170.4mA
-800mV    62.24mA    44.68mA    97.43mA
-140mV    9.467mA    6.582mA    15.76mA
25mV      -1.58mA    -1.08mA    -2.674mA
190mV     -10.93mA   -7.424mA   -18.66mA
355mV     -18.44mA   -12.42mA   -31.8mA
520mV     -24.17mA   -16.11mA   -42.18mA
795mV     -29.88mA   -19.49mA   -53.5mA
1.07V     -31.75mA   -20.4mA    -58.22mA
3.6V      -37.02mA   -23.42mA   -69.39mA
[GND_clamp]
|Voltage   I(typ)   I(min)   I(max)
-1.8V     -1.677A    -1.372A    -2.207A
-1.097V   -411.6mA   -430.5mA   -392.9mA
-1.06V    -351mA     -384.7mA   -309.8mA
-986mV    -235.9mA   -295.9mA   -164.7mA
-949mV    -183mA     -253.4mA   -113mA
-912mV    -135mA     -212.5mA   -83.33mA
-838mV    -63.16mA   -137.2mA   -62.66mA
-801mV    -43.93mA   -103.8mA   -56.25mA
-690mV    -21.49mA   -30.06mA   -34.72mA
-579mV    -9.043mA   -5.343mA   -15.31mA
-357mV    -110.3uA   -52.32uA   -166.6uA
1.8V      0A         0A         0A
[POWER_clamp]
|Voltage   I(typ)   I(min)   I(max)
-1.8V     22.96mA    14.12mA    42.58mA
-1.604V   19.99mA    12.25mA    37.59mA
-1.419V   16.97mA    10.35mA    32.49mA
-975mV    9.199mA    5.527mA    19.24mA
-864mV    7.174mA    4.324mA    15.6mA
-790mV    5.788mA    3.534mA    12.79mA
-679mV    3.605mA    2.374mA    7.249mA
-605mV    2.066mA    1.631mA    3.958mA
-531mV    820.6uA    942.6uA    1.61mA
-457mV    221.3uA    381uA      405.2uA
-272mV    4.708uA    6.259uA    4.369uA
1.8V      0A         0A         4.229nA
[Ramp]
| variable   typ   min   max
dV/dt_r   0.750/0.490n   0.575/0.977n   0.928/0.217n
dV/dt_f   0.770/0.824n   0.550/1.665n   0.933/0.367n
R_load = 50.000
[Rising Waveform]
R_fixture= 50.000
V_fixture= 0.0
V_fixture_min= 0.0
V_fixture_max= 0.0
|time   V(typ)   V(min)   V(max)
0s        2.942nV    32.1nV     1.699nV
880ps     -81.65uV   23.9uV     -10.92mV
975ps     -901.9uV   -1.059uV   200.6mV
1.256ns   -26.41mV   125.1uV    1.325V
1.718ns   27.48mV    -906.2uV   1.523V
2.425ns   1.039V     -11.82mV   1.544V
3.187ns   1.225V     67.73mV    1.547V
4.313ns   1.247V     753.1mV    1.547V
5.434ns   1.25V      923.9mV    1.547V
20ns      1.25V      958.6mV    1.547V
[Rising Waveform]
R_fixture= 50.000
V_fixture= 1.800
V_fixture_min= 1.710
V_fixture_max= 1.890
|time   V(typ)   V(min)   V(max)
0s        516.8mV    793.5mV    334.2mV
629ps     516.8mV    793.5mV    344.6mV
774ps     516.7mV    793.5mV    1.021V
1.034ns   509.9mV    793.5mV    1.727V
1.169ns   592.6mV    793.3mV    1.845V
1.326ns   1.16V      792.9mV    1.871V
1.942ns   1.741V     808.6mV    1.887V
2.361ns   1.789V     1.494V     1.889V
3.419ns   1.799V     1.686V     1.89V
20ns      1.8V       1.71V      1.89V
[Falling Waveform]
R_fixture= 50.000
V_fixture= 1.800
V_fixture_min= 1.710
V_fixture_max= 1.890
|time   V(typ)   V(min)   V(max)
0s        1.8V       1.71V      1.89V
928ps     1.8V       1.71V      1.905V
1.504ns   1.846V     1.71V      581.6mV
1.864ns   1.761V     1.711V     380.9mV
2.111ns   1.55V      1.71V      355mV
2.892ns   799.3mV    1.72V      336.2mV
3.953ns   547.7mV    1.484V     334.4mV
5.084ns   521.3mV    1.071V     334.2mV
6.556ns   517.2mV    857.8mV    334.2mV
20ns      516.8mV    793.5mV    334.2mV
[Falling Waveform]
R_fixture= 50.000
V_fixture= 0.0
V_fixture_min= 0.0
V_fixture_max= 0.0
|time   V(typ)   V(min)   V(max)
0s        1.25V      958.6mV    1.547V
673ps     1.25V      958.6mV    1.544V
1.066ns   1.25V      958.6mV    247.6mV
1.253ns   1.211V     958.6mV    39.39mV
1.374ns   799.7mV    958.6mV    19.13mV
1.978ns   91.58mV    957.8mV    2.264mV
2.245ns   24.39mV    895.9mV    1.153mV
2.672ns   6.385mV    215.6mV    298.9uV
3.652ns   904.6uV    20.41mV    65.68uV
20ns      46.49nV    185.6nV    11.87nV
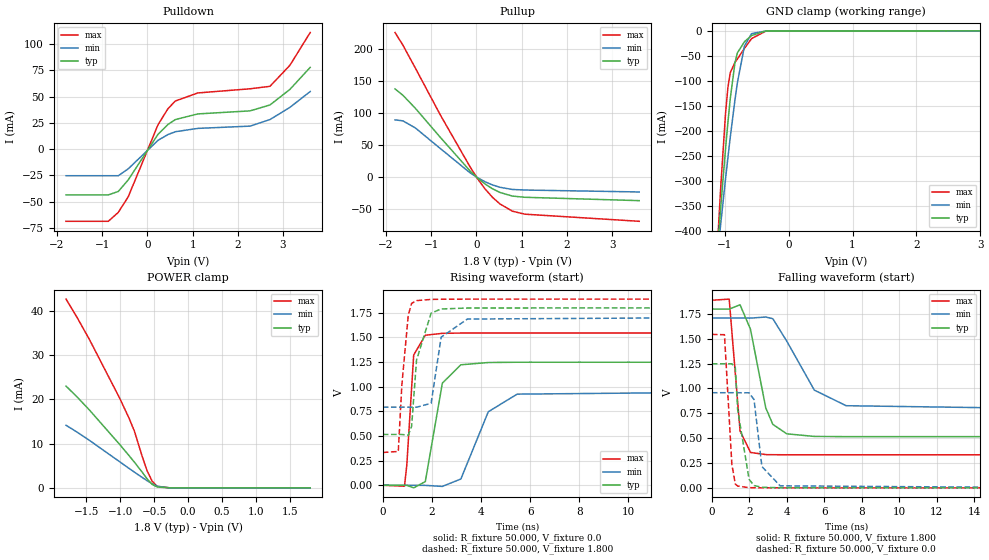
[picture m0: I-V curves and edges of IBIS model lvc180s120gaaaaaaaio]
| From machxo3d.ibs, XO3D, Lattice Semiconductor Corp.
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|   Model lvc180s120gaaaaaaaio
[Model] lvc180s120gaaaaaaaio
Model_type I/O
Polarity   Non-Inverting
Enable   Active-Low
Vinl =  0.630V
Vinh =  1.170V
Vmeas =  0.900V
Cref =  0.0F
Rref =  1.000M
Vref =  0.0V
C_comp   4.200pF   3.800pF   7.500pF
[Temperature Range]   25.000   0.105k   -40.000
[Voltage Range]   1.800V   1.710V   1.890V
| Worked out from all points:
|   slope of the pulldown table from 0 to 0.27 V, typ, clamps not added: 17 ohm
|   slope of the pullup table from 0 to 0.27 V, typ, clamps not added: 18.2 ohm
|   GND clamp passes 1 mA (typ) near -0.44 V on its own axis
|   POWER clamp passes 1 mA (typ) near -0.55 V on its own axis
|   rising waveform, R_fixture 50.000, V_fixture 0.0: 20-80 % time 494ps typ, 984ps min, 220ps max; typ from 0 V to 1.25 V
|   rising waveform, R_fixture 50.000, V_fixture 1.800: 20-80 % time 369ps typ, 366ps min, 283ps max; typ from 0.515 V to 1.8 V
|   falling waveform, R_fixture 50.000, V_fixture 1.800: 20-80 % time 829ps typ, 1.67ns min, 367ps max; typ from 1.8 V to 0.515 V
|   falling waveform, R_fixture 50.000, V_fixture 0.0: 20-80 % time 368ps typ, 399ps min, 305ps max; typ from 1.25 V to 0 V
[Pulldown]
|Voltage   I(typ)   I(min)   I(max)
-1.8V     -43.56mA   -25.31mA   -68.69mA
-865mV    -43.56mA   -25.31mA   -68.69mA
-645mV    -40.3mA    -25.31mA   -60.23mA
-425mV    -29.3mA    -18.76mA   -45.41mA
235mV     14.17mA    8.428mA    23.27mA
455mV     23.55mA    13.92mA    38.6mA
620mV     28.2mA     16.61mA    45.89mA
1.115V    33.55mA    19.77mA    53.52mA
2.27V     36.44mA    21.92mA    57.47mA
2.71V     42.06mA    28.16mA    59.82mA
3.15V     56.83mA    39.74mA    79.77mA
3.6V      77.82mA    54.86mA    111mA
[Pullup]
|Voltage   I(typ)   I(min)   I(max)
-1.8V     138mA      89.55mA    226.3mA
-1.625V   128mA      87.95mA    206.4mA
-1.35V    107.6mA    76.85mA    170.5mA
-800mV    62.24mA    44.68mA    97.43mA
-140mV    9.467mA    6.582mA    15.76mA
25mV      -1.58mA    -1.08mA    -2.674mA
190mV     -10.93mA   -7.424mA   -18.66mA
355mV     -18.44mA   -12.42mA   -31.8mA
520mV     -24.17mA   -16.11mA   -42.18mA
795mV     -29.88mA   -19.49mA   -53.5mA
1.07V     -31.75mA   -20.4mA    -58.22mA
3.6V      -37.02mA   -23.42mA   -69.38mA
[GND_clamp]
|Voltage   I(typ)   I(min)   I(max)
-1.8V     -1.677A    -1.372A    -2.207A
-1.097V   -411.7mA   -430.5mA   -393mA
-1.06V    -351mA     -384.7mA   -309.9mA
-986mV    -235.9mA   -295.9mA   -164.8mA
-949mV    -183mA     -253.4mA   -113.1mA
-912mV    -135mA     -212.5mA   -83.39mA
-838mV    -63.2mA    -137.2mA   -62.73mA
-801mV    -43.97mA   -103.8mA   -56.32mA
-690mV    -21.54mA   -30.09mA   -34.79mA
-579mV    -9.102mA   -5.388mA   -15.4mA
-357mV    -191.3uA   -96.81uA   -298.1uA
3.6V      109.7uA    43.11uA    257.2uA
[POWER_clamp]
|Voltage   I(typ)   I(min)   I(max)
-1.8V     23.01mA    14.15mA    42.67mA
-1.641V   20.61mA    12.64mA    38.63mA
-1.456V   17.62mA    10.75mA    33.57mA
-1.012V   9.864mA    5.936mA    20.36mA
-864mV    7.162mA    4.325mA    15.53mA
-790mV    5.771mA    3.533mA    12.74mA
-679mV    3.583mA    2.37mA     7.204mA
-605mV    2.041mA    1.626mA    3.889mA
-531mV    791.7uA    936.7uA    1.526mA
-457mV    198.5uA    375.7uA    334.5uA
-272mV    2.958uA    5.534uA    1.322uA
1.8V      0A         0A         0A
[Ramp]
| variable   typ   min   max
dV/dt_r   0.749/0.492n   0.574/0.975n   0.927/0.218n
dV/dt_f   0.770/0.822n   0.550/1.672n   0.933/0.367n
R_load = 50.000
[Rising Waveform]
R_fixture= 50.000
V_fixture= 0.0
V_fixture_min= 0.0
V_fixture_max= 0.0
|time   V(typ)   V(min)   V(max)
0s        2.84nV     31.79nV    1.575nV
881ps     -70.9uV    23.86uV    -9.625mV
977ps     -843uV     -1.091uV   208mV
1.256ns   -26.36mV   124.9uV    1.321V
1.73ns    37.17mV    -1.094mV   1.522V
2.424ns   1.036V     -11.75mV   1.541V
3.178ns   1.222V     63.3mV     1.544V
4.296ns   1.245V     745.9mV    1.544V
5.47ns    1.248V     924.3mV    1.544V
20ns      1.248V     957.3mV    1.544V
[Rising Waveform]
R_fixture= 50.000
V_fixture= 1.800
V_fixture_min= 1.710
V_fixture_max= 1.890
|time   V(typ)   V(min)   V(max)
0s        515.2mV    792.2mV    332.7mV
629ps     515.2mV    792.2mV    342.9mV
774ps     515mV      792.2mV    1.016V
1.034ns   508.3mV    792.2mV    1.722V
1.172ns   598mV      792mV      1.845V
1.372ns   1.269V     791.7mV    1.873V
1.966ns   1.746V     831.2mV    1.885V
2.375ns   1.788V     1.502V     1.887V
3.444ns   1.798V     1.686V     1.888V
20ns      1.799V     1.709V     1.888V
[Falling Waveform]
R_fixture= 50.000
V_fixture= 1.800
V_fixture_min= 1.710
V_fixture_max= 1.890
|time   V(typ)   V(min)   V(max)
0s        1.799V     1.709V     1.888V
925ps     1.799V     1.709V     1.899V
1.505ns   1.842V     1.709V     573.1mV
2.063ns   1.595V     1.708V     356.4mV
2.877ns   804.8mV    1.719V     334.7mV
3.254ns   638.9mV    1.702V     333.6mV
3.999ns   543.6mV    1.476V     332.8mV
5.471ns   517.5mV    983.3mV    332.8mV
7.169ns   515.4mV    826.6mV    332.7mV
20ns      515.2mV    792.2mV    332.7mV
[Falling Waveform]
R_fixture= 50.000
V_fixture= 0.0
V_fixture_min= 0.0
V_fixture_max= 0.0
|time   V(typ)   V(min)   V(max)
0s        1.248V     957.3mV    1.544V
673ps     1.248V     957.4mV    1.541V
1.066ns   1.248V     957.3mV    240.1mV
1.25ns    1.214V     957.3mV    38.76mV
1.376ns   789.6mV    957.3mV    18.39mV
1.985ns   86.41mV    956.6mV    2.169mV
2.249ns   23.43mV    888.7mV    1.08mV
2.672ns   6.322mV    214.2mV    378.9uV
3.645ns   904.5uV    20.49mV    52.21uV
20ns      43.79nV    181.7nV    2.491nV
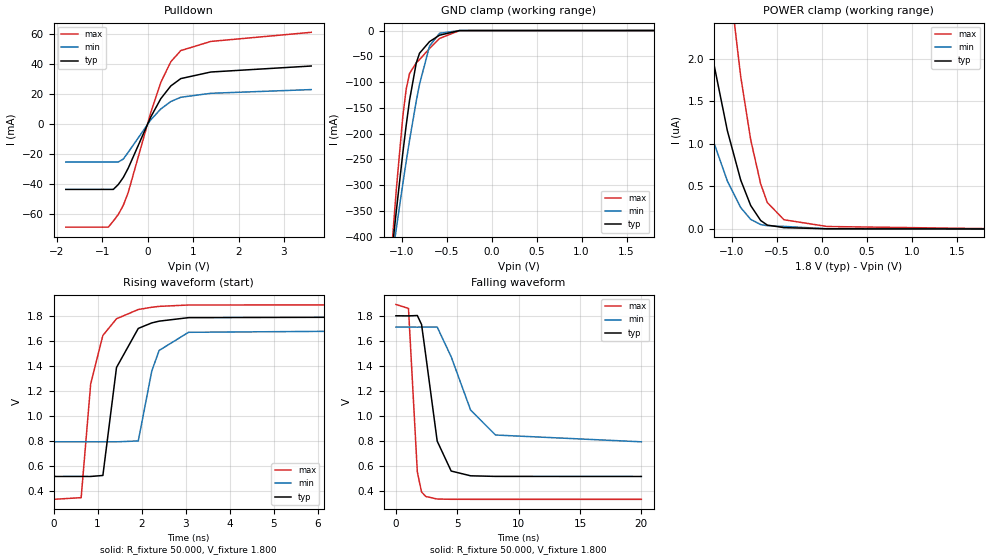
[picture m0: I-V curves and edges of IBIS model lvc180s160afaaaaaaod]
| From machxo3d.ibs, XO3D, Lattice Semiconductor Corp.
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|   Model lvc180s160afaaaaaaod
[Model] lvc180s160afaaaaaaod
Model_type I/O_open_drain
Polarity   Non-Inverting
Enable   Active-Low
Vinl =  0.630V
Vinh =  1.170V
Vmeas =  0.900V
Cref =  0.0F
Rref = 10.00k
Vref = 1.80V
C_comp   4.200pF   3.800pF   7.500pF
[Temperature Range]   25.000   0.105k   -40.000
[Voltage Range]   1.800V   1.710V   1.890V
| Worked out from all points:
|   slope of the pulldown table from 0 to 0.27 V, typ, clamps not added: 17 ohm
|   GND clamp passes 1 mA (typ) near -0.44 V on its own axis
|   rising waveform, R_fixture 50.000, V_fixture 1.800: 20-80 % time 342ps typ, 354ps min, 347ps max; typ from 0.517 V to 1.8 V
|   falling waveform, R_fixture 50.000, V_fixture 1.800: 20-80 % time 1.07ns typ, 2.21ns min, 463ps max; typ from 1.8 V to 0.517 V
[Pulldown]
|Voltage   I(typ)   I(min)   I(max)
-1.8V     -43.56mA   -25.31mA   -68.69mA
-865mV    -43.56mA   -25.31mA   -68.69mA
-755mV    -43.56mA   -25.31mA   -64.67mA
-645mV    -40.3mA    -25.31mA   -60.23mA
-535mV    -35.61mA   -23.32mA   -54.19mA
-425mV    -29.3mA    -18.76mA   -45.41mA
70mV      4.681mA    2.794mA    7.693mA
290mV     16.86mA    10.01mA    27.69mA
510mV     25.33mA    14.95mA    41.43mA
730mV     30.23mA    17.79mA    48.88mA
1.39V     34.61mA    20.44mA    54.98mA
3.6V      38.61mA    22.91mA    61.04mA
[GND_clamp]
|Voltage   I(typ)   I(min)   I(max)
-1.8V     -1.677A    -1.372A    -2.207A
-1.097V   -411.6mA   -430.5mA   -392.9mA
-1.06V    -351mA     -384.7mA   -309.8mA
-986mV    -235.9mA   -295.9mA   -164.7mA
-949mV    -183mA     -253.4mA   -113mA
-912mV    -135mA     -212.5mA   -83.33mA
-838mV    -63.16mA   -137.2mA   -62.66mA
-801mV    -43.93mA   -103.8mA   -56.25mA
-690mV    -21.49mA   -30.06mA   -34.72mA
-579mV    -9.043mA   -5.343mA   -15.31mA
-357mV    -110.3uA   -52.32uA   -166.6uA
1.8V      0A         0A         0A
[POWER_clamp]
|Voltage   I(typ)   I(min)   I(max)
-1.8V     6.918uA    4.075uA    15.53uA
-1.641V   5.335uA    3.081uA    12.17uA
-1.382V   3.16uA     1.741uA    7.507uA
-1.197V   1.931uA    1.01uA     4.843uA
-1.049V   1.156uA    564.3nA    3.128uA
-901mV    576.3nA    251.8nA    1.796uA
-790mV    276.2nA    113.3nA    1.051uA
-679mV    99.6nA     51.82nA    530.4nA
-605mV    45.39nA    37.94nA    310.9nA
-420mV    15.42nA    30.13nA    108.3nA
61mV      1.594nA    2.49nA     28.82nA
1.8V      0A         0A         4.229nA
[Ramp]
| variable   typ   min   max
dV/dt_r   0.770/0.342n   0.550/0.355n   0.933/0.346n
dV/dt_f   0.770/1.067n   0.550/2.191n   0.933/0.464n
R_load = 50.000
[Rising Waveform]
R_fixture= 50.000
V_fixture= 1.800
V_fixture_min= 1.710
V_fixture_max= 1.890
|time   V(typ)   V(min)   V(max)
0s        516.8mV    793.5mV    334.2mV
627ps     516.9mV    793.5mV    347.6mV
843ps     516.8mV    793.5mV    1.255V
1.12ns    524.8mV    793.4mV    1.643V
1.429ns   1.387V     793.2mV    1.776V
1.923ns   1.699V     800.5mV    1.85V
2.229ns   1.743V     1.358V     1.868V
2.396ns   1.757V     1.523V     1.875V
3.063ns   1.785V     1.668V     1.886V
20ns      1.8V       1.71V      1.89V
[Falling Waveform]
R_fixture= 50.000
V_fixture= 1.800
V_fixture_min= 1.710
V_fixture_max= 1.890
|time   V(typ)   V(min)   V(max)
0s        1.8V       1.71V      1.89V
1.023ns   1.799V     1.71V      1.859V
1.744ns   1.802V     1.709V     552.7mV
2.09ns    1.73V      1.71V      392.4mV
2.441ns   1.477V     1.71V      356.8mV
3.363ns   799.3mV    1.71V      336.7mV
4.501ns   560.2mV    1.473V     334.5mV
6.086ns   522.1mV    1.047V     334.2mV
8.115ns   517.3mV    847.8mV    334.2mV
20ns      516.8mV    793.5mV    334.2mV
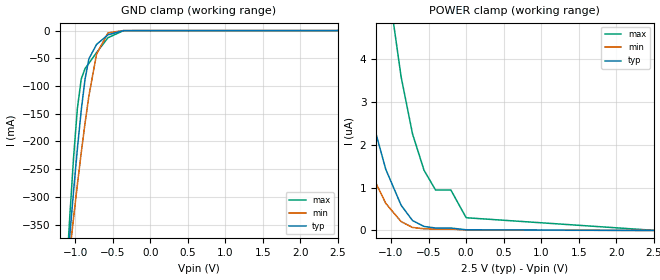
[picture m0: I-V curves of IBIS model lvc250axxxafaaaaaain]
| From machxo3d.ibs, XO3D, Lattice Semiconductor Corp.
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|   Model lvc250axxxafaaaaaain
[Model] lvc250axxxafaaaaaain
Model_type Input
Polarity   Non-Inverting
Enable   Active-High
Vinl =  0.700V
Vinh =  1.700V
C_comp   4.200pF   3.800pF   7.500pF
[Temperature Range]   25.000   0.105k   -40.000
[Voltage Range]   2.500V   2.380V   2.630V
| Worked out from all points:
|   GND clamp passes 1 mA (typ) near -0.43 V on its own axis
[GND_clamp]
|Voltage   I(typ)   I(min)   I(max)
-2.5V     -2.99A     -2.35A     -4.091A
-1.123V   -455.1mA   -463.2mA   -453.6mA
-1.072V   -370.5mA   -399.5mA   -336.3mA
-1.021V   -289.1mA   -337.4mA   -228.5mA
-970mV    -212.5mA   -277.3mA   -139.9mA
-919mV    -143.6mA   -220.1mA   -87.34mA
-868mV    -87.34mA   -166.5mA   -68.39mA
-817mV    -50.9mA    -117.8mA   -59.06mA
-715mV    -24.94mA   -42.34mA   -39.63mA
-562mV    -7.547mA   -4.077mA   -12.85mA
-358mV    -114uA     -53.77uA   -172.8uA
2.5V      0A         0A         0A
[POWER_clamp]
|Voltage   I(typ)   I(min)   I(max)
-2.5V     16.57uA    10.06uA    44.17uA
-2.09V    10.8uA     6.285uA    30.12uA
-1.682V   6.109uA    3.358uA    18.45uA
-1.376V   3.384uA    1.736uA    11.44uA
-1.07V    1.428uA    632.9nA    6.128uA
-866mV    590.6nA    207.8nA    3.594uA
-713mV    230.3nA    70.52nA    2.252uA
-560mV    93.25nA    39.02nA    1.406uA
-407mV    57.68nA    33.41nA    946.1nA
-203mV    57.68nA    32.4nA     946.1nA
1mV       16.07nA    10.57nA    297.5nA
2.5V      0A         0A         3.665nA
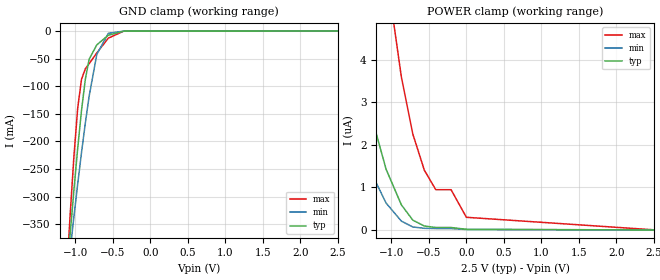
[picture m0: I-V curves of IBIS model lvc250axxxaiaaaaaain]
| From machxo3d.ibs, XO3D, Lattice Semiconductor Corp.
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|   Model lvc250axxxaiaaaaaain
[Model] lvc250axxxaiaaaaaain
Model_type Input
Polarity   Non-Inverting
Enable   Active-High
Vinl =  0.700V
Vinh =  1.700V
C_comp   4.200pF   3.800pF   7.500pF
[Temperature Range]   25.000   0.105k   -40.000
[Voltage Range]   2.500V   2.380V   2.630V
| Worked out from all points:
|   GND clamp passes 1 mA (typ) near -0.43 V on its own axis
[GND_clamp]
|Voltage   I(typ)   I(min)   I(max)
-2.5V     -2.99A     -2.35A     -4.091A
-1.123V   -455.1mA   -463.2mA   -453.6mA
-1.072V   -370.5mA   -399.5mA   -336.2mA
-1.021V   -289.1mA   -337.4mA   -228.5mA
-970mV    -212.5mA   -277.3mA   -139.8mA
-919mV    -143.6mA   -220.1mA   -87.28mA
-868mV    -87.31mA   -166.5mA   -68.34mA
-817mV    -50.87mA   -117.8mA   -59.02mA
-715mV    -24.91mA   -42.33mA   -39.58mA
-562mV    -7.531mA   -4.077mA   -12.82mA
-358mV    -112.5uA   -53.7uA    -162uA
2.5V      0A         0A         0A
[POWER_clamp]
|Voltage   I(typ)   I(min)   I(max)
-2.5V     16.57uA    10.06uA    44.17uA
-2.09V    10.8uA     6.285uA    30.12uA
-1.682V   6.109uA    3.358uA    18.45uA
-1.376V   3.384uA    1.736uA    11.45uA
-1.07V    1.428uA    632.9nA    6.128uA
-866mV    590.7nA    207.8nA    3.594uA
-713mV    230.3nA    70.53nA    2.252uA
-560mV    93.28nA    39.04nA    1.406uA
-407mV    57.7nA     33.42nA    946.1nA
-203mV    57.7nA     32.41nA    946.1nA
1mV       16.07nA    10.59nA    297.5nA
2.5V      0A         0A         3.655nA
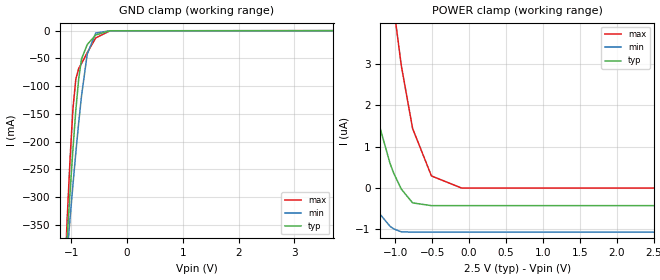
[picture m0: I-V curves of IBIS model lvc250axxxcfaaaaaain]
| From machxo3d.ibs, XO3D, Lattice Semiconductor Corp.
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|   Model lvc250axxxcfaaaaaain
[Model] lvc250axxxcfaaaaaain
Model_type Input
Polarity   Non-Inverting
Enable   Active-High
Vinl =  0.700V
Vinh =  1.700V
C_comp   4.200pF   3.800pF   7.500pF
[Temperature Range]   25.000   0.105k   -40.000
[Voltage Range]   2.500V   2.380V   2.630V
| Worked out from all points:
|   GND clamp passes 1 mA (typ) near -0.43 V on its own axis
[GND_clamp]
|Voltage   I(typ)   I(min)   I(max)
-2.5V     -2.99A     -2.35A     -4.091A
-1.123V   -455.1mA   -463.2mA   -453.7mA
-1.072V   -370.5mA   -399.5mA   -336.3mA
-1.021V   -289.2mA   -337.4mA   -228.6mA
-970mV    -212.6mA   -277.4mA   -140mA
-919mV    -143.6mA   -220.1mA   -87.4mA
-868mV    -87.38mA   -166.5mA   -68.45mA
-817mV    -50.94mA   -117.8mA   -59.13mA
-715mV    -24.99mA   -42.37mA   -39.7mA
-562mV    -7.607mA   -4.125mA   -12.95mA
-307mV    -97.65uA   -51.76uA   -173.8uA
5V        114uA      49.33uA    266.8uA
[POWER_clamp]
|Voltage   I(typ)   I(min)   I(max)
-2.5V     22.27uA    8.765uA    64.97uA
-2.141V   14.04uA    4.842uA    43.67uA
-1.835V   8.45uA     2.291uA    28.47uA
-1.58V    4.902uA    739nA      18.31uA
-1.274V   1.888uA    -483.2nA   9.321uA
-1.07V    594.8nA    -921.9nA   5.173uA
-1.019V   355.5nA    -985.6nA   4.351uA
-917mV    -26.04nA   -1.057uA   2.951uA
-764mV    -358.4nA   -1.063uA   1.434uA
-509mV    -424.5nA   -1.063uA   291.6nA
-101mV    -424.5nA   -1.063uA   0A
2.5V      -424.5nA   -1.063uA   0A
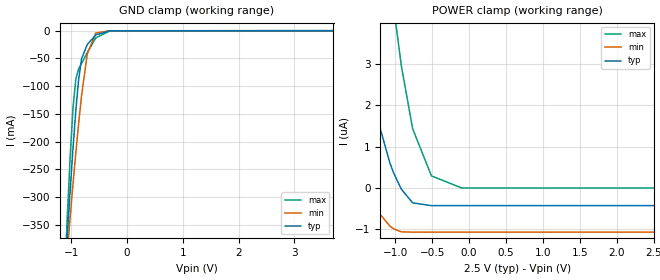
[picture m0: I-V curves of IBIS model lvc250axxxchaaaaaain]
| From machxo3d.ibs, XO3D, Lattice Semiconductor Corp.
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|   Model lvc250axxxchaaaaaain
[Model] lvc250axxxchaaaaaain
Model_type Input
Polarity   Non-Inverting
Enable   Active-High
Vinl =  0.700V
Vinh =  1.700V
C_comp   4.200pF   3.800pF   7.500pF
[Temperature Range]   25.000   0.105k   -40.000
[Voltage Range]   2.500V   2.380V   2.630V
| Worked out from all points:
|   GND clamp passes 1 mA (typ) near -0.43 V on its own axis
[GND_clamp]
|Voltage   I(typ)   I(min)   I(max)
-2.5V     -2.99A     -2.35A     -4.091A
-1.123V   -455.1mA   -463.2mA   -453.7mA
-1.072V   -370.5mA   -399.5mA   -336.3mA
-1.021V   -289.1mA   -337.4mA   -228.6mA
-970mV    -212.6mA   -277.4mA   -139.9mA
-919mV    -143.6mA   -220.1mA   -87.38mA
-868mV    -87.37mA   -166.5mA   -68.43mA
-817mV    -50.93mA   -117.8mA   -59.11mA
-715mV    -24.98mA   -42.37mA   -39.68mA
-562mV    -7.602mA   -4.126mA   -12.93mA
-307mV    -97.54uA   -51.75uA   -172.5uA
5V        114uA      49.33uA    266.8uA
[POWER_clamp]
|Voltage   I(typ)   I(min)   I(max)
-2.5V     22.27uA    8.762uA    64.97uA
-2.141V   14.03uA    4.84uA     43.67uA
-1.835V   8.45uA     2.289uA    28.47uA
-1.58V    4.901uA    737.2nA    18.31uA
-1.274V   1.887uA    -484.6nA   9.321uA
-1.07V    594.4nA    -923.1nA   5.173uA
-1.019V   355.1nA    -986.8nA   4.351uA
-917mV    -26.38nA   -1.058uA   2.951uA
-764mV    -358.6nA   -1.064uA   1.434uA
-509mV    -424.7nA   -1.064uA   291.6nA
-101mV    -424.7nA   -1.064uA   0A
2.5V      -424.7nA   -1.064uA   0A
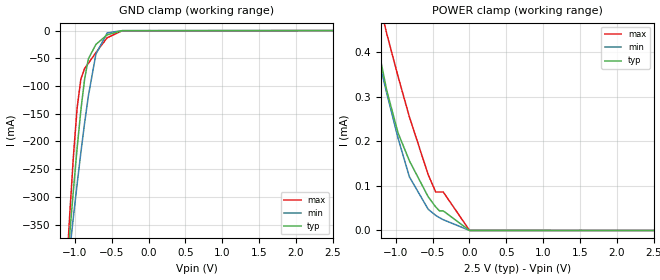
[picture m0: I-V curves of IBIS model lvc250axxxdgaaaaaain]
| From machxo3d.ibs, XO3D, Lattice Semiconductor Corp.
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|   Model lvc250axxxdgaaaaaain
[Model] lvc250axxxdgaaaaaain
Model_type Input
Polarity   Non-Inverting
Enable   Active-High
Vinl =  0.700V
Vinh =  1.700V
C_comp   4.200pF   3.800pF   7.500pF
[Temperature Range]   25.000   0.105k   -40.000
[Voltage Range]   2.500V   2.380V   2.630V
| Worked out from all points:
|   GND clamp passes 1 mA (typ) near -0.43 V on its own axis
|   POWER clamp passes 1 mA (typ) near -1.90 V on its own axis
[GND_clamp]
|Voltage   I(typ)   I(min)   I(max)
-2.5V     -2.99A     -2.35A     -4.091A
-1.123V   -455.1mA   -463.2mA   -453.7mA
-1.072V   -370.5mA   -399.5mA   -336.3mA
-1.021V   -289.2mA   -337.4mA   -228.6mA
-970mV    -212.6mA   -277.4mA   -140mA
-919mV    -143.6mA   -220.1mA   -87.4mA
-868mV    -87.39mA   -166.5mA   -68.45mA
-817mV    -50.94mA   -117.8mA   -59.13mA
-715mV    -24.99mA   -42.37mA   -39.7mA
-562mV    -7.608mA   -4.125mA   -12.95mA
-358mV    -194.9uA   -98.36uA   -303.6uA
2.5V      13.17nA    0A         -19.29uA
[POWER_clamp]
|Voltage   I(typ)   I(min)   I(max)
-2.5V     1.538mA    1.365mA    2.125mA
-1.325V   482.6uA    450.2uA    591.5uA
-1.274V   438.4uA    413.8uA    546.6uA
-1.121V   313.5uA    307.1uA    441uA
-968mV    218.6uA    206.5uA    345.2uA
-815mV    156.3uA    120.3uA    254.8uA
-560mV    75.6uA     47.55uA    125.2uA
-458mV    52.75uA    33.88uA    86.35uA
-407mV    44.01uA    28.68uA    86.35uA
-356mV    44.01uA    24.21uA    86.35uA
1mV       0A         0A         141nA
2.5V      0A         0A         0A
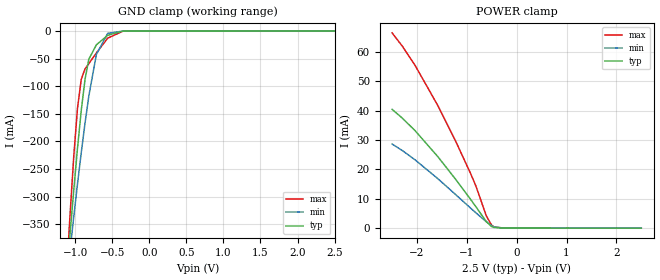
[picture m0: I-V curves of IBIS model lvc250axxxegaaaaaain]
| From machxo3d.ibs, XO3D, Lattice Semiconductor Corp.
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|   Model lvc250axxxegaaaaaain
[Model] lvc250axxxegaaaaaain
Model_type Input
Polarity   Non-Inverting
Enable   Active-High
Vinl =  0.700V
Vinh =  1.700V
C_comp   4.200pF   3.800pF   7.500pF
[Temperature Range]   25.000   0.105k   -40.000
[Voltage Range]   2.500V   2.380V   2.630V
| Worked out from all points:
|   GND clamp passes 1 mA (typ) near -0.43 V on its own axis
|   POWER clamp passes 1 mA (typ) near -0.54 V on its own axis
[GND_clamp]
|Voltage   I(typ)   I(min)   I(max)
-2.5V     -2.99A     -2.35A     -4.091A
-1.123V   -455.1mA   -463.2mA   -453.6mA
-1.072V   -370.5mA   -399.5mA   -336.3mA
-1.021V   -289.1mA   -337.4mA   -228.5mA
-970mV    -212.6mA   -277.3mA   -139.9mA
-919mV    -143.6mA   -220.1mA   -87.34mA
-868mV    -87.35mA   -166.5mA   -68.39mA
-817mV    -50.9mA    -117.8mA   -59.07mA
-715mV    -24.94mA   -42.34mA   -39.63mA
-562mV    -7.547mA   -4.077mA   -12.85mA
-358mV    -114uA     -53.77uA   -172.8uA
2.5V      0A         0A         0A
[POWER_clamp]
|Voltage   I(typ)   I(min)   I(max)
-2.5V     40.49mA    28.66mA    66.53mA
-2.294V   37.48mA    26.44mA    61.99mA
-2.039V   33.22mA    23.28mA    55.47mA
-1.58V    24.32mA    16.83mA    41.7mA
-1.223V   16.6mA     11.41mA    29.58mA
-917mV    9.616mA    6.712mA    18.32mA
-815mV    7.205mA    5.171mA    14.19mA
-611mV    2.275mA    2.213mA    4.254mA
-509mV    589.4uA    929.1uA    1.152mA
-458mV    232.9uA    445.2uA    427.7uA
-254mV    3.785uA    4.472uA    4.114uA
2.5V      0A         0A         3.667nA
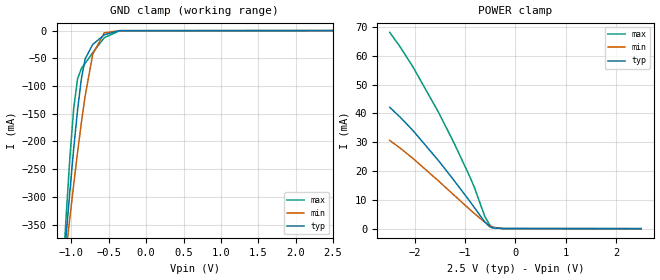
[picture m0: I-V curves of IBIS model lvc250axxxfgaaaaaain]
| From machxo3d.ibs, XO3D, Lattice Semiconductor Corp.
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|   Model lvc250axxxfgaaaaaain
[Model] lvc250axxxfgaaaaaain
Model_type Input
Polarity   Non-Inverting
Enable   Active-High
Vinl =  0.700V
Vinh =  1.700V
C_comp   4.200pF   3.800pF   7.500pF
[Temperature Range]   25.000   0.105k   -40.000
[Voltage Range]   2.500V   2.380V   2.630V
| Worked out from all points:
|   GND clamp passes 1 mA (typ) near -0.43 V on its own axis
|   POWER clamp passes 1 mA (typ) near -0.54 V on its own axis
[GND_clamp]
|Voltage   I(typ)   I(min)   I(max)
-2.5V     -2.99A     -2.35A     -4.091A
-1.123V   -455.1mA   -463.2mA   -453.7mA
-1.072V   -370.5mA   -399.5mA   -336.3mA
-1.021V   -289.2mA   -337.4mA   -228.6mA
-970mV    -212.6mA   -277.4mA   -140mA
-919mV    -143.6mA   -220.1mA   -87.39mA
-868mV    -87.38mA   -166.5mA   -68.44mA
-817mV    -50.93mA   -117.8mA   -59.12mA
-715mV    -24.98mA   -42.36mA   -39.69mA
-562mV    -7.596mA   -4.111mA   -12.93mA
-358mV    -193.4uA   -101.2uA   -309.3uA
2.5V      13.17nA    0A         -19.29uA
[POWER_clamp]
|Voltage   I(typ)   I(min)   I(max)
-2.5V     42.14mA    30.66mA    68.15mA
-2.294V   38.75mA    27.99mA    63.15mA
-2.039V   34.09mA    24.4mA     56.2mA
-1.529V   23.59mA    16.56mA    40.38mA
-1.223V   16.79mA    11.66mA    29.8mA
-917mV    9.72mA     6.817mA    18.42mA
-815mV    7.285mA    5.246mA    14.27mA
-611mV    2.32mA     2.253mA    4.314mA
-509mV    627.1uA    959.6uA    1.202mA
-458mV    269.3uA    472.4uA    476.3uA
-254mV    28.45uA    20.72uA    43.74uA
2.5V      0A         0A         0A
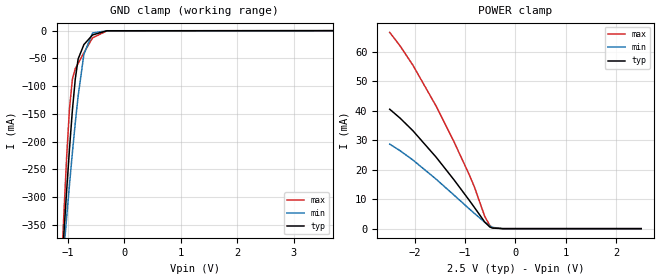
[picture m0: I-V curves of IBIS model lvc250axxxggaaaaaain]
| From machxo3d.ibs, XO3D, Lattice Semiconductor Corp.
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|   Model lvc250axxxggaaaaaain
[Model] lvc250axxxggaaaaaain
Model_type Input
Polarity   Non-Inverting
Enable   Active-High
Vinl =  0.700V
Vinh =  1.700V
C_comp   4.200pF   3.800pF   7.500pF
[Temperature Range]   25.000   0.105k   -40.000
[Voltage Range]   2.500V   2.380V   2.630V
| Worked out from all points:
|   GND clamp passes 1 mA (typ) near -0.43 V on its own axis
|   POWER clamp passes 1 mA (typ) near -0.54 V on its own axis
[GND_clamp]
|Voltage   I(typ)   I(min)   I(max)
-2.5V     -2.99A     -2.35A     -4.091A
-1.123V   -455.1mA   -463.2mA   -453.7mA
-1.072V   -370.5mA   -399.5mA   -336.3mA
-1.021V   -289.2mA   -337.4mA   -228.6mA
-970mV    -212.6mA   -277.4mA   -140mA
-919mV    -143.6mA   -220.1mA   -87.4mA
-868mV    -87.39mA   -166.5mA   -68.45mA
-817mV    -50.94mA   -117.8mA   -59.13mA
-715mV    -24.99mA   -42.37mA   -39.7mA
-562mV    -7.608mA   -4.125mA   -12.95mA
-307mV    -97.66uA   -51.76uA   -173.8uA
5V        114uA      49.35uA    266.8uA
[POWER_clamp]
|Voltage   I(typ)   I(min)   I(max)
-2.5V     40.55mA    28.7mA     66.64mA
-2.294V   37.53mA    26.47mA    62.05mA
-2.039V   33.25mA    23.31mA    55.5mA
-1.58V    24.33mA    16.84mA    41.69mA
-1.223V   16.6mA     11.41mA    29.54mA
-917mV    9.596mA    6.709mA    18.24mA
-815mV    7.18mA     5.166mA    14.11mA
-611mV    2.243mA    2.205mA    4.167mA
-509mV    558uA      921.7uA    1.059mA
-458mV    208uA      438.7uA    350.8uA
-254mV    2.162uA    3.635uA    1.029uA
2.5V      0A         0A         0A
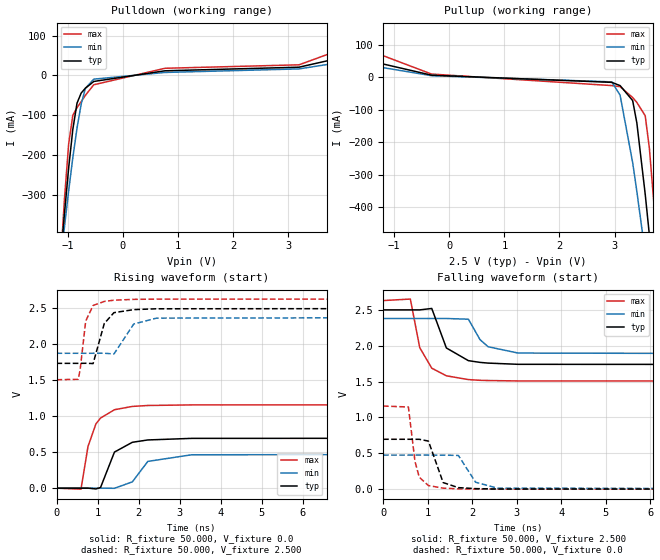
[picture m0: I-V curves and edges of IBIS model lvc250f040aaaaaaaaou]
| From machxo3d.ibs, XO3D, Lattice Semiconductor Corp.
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|   Model lvc250f040aaaaaaaaou
[Model] lvc250f040aaaaaaaaou
Model_type Output
Polarity   Non-Inverting
Enable   Active-High
Vmeas =  1.250V
Cref =  0.0F
Rref =  1.000M
Vref =  0.0V
C_comp   4.200pF   3.800pF   7.500pF
[Temperature Range]   25.000   0.105k   -40.000
[Voltage Range]   2.500V   2.380V   2.630V
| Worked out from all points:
|   slope of the pulldown table from 0 to 0.375 V, typ, clamps not added: 54.4 ohm
|   slope of the pullup table from 0 to 0.375 V, typ, clamps not added: 65.1 ohm
|   rising waveform, R_fixture 50.000, V_fixture 0.0: 20-80 % time 366ps typ, 401ps min, 329ps max; typ from 0 V to 0.696 V
|   rising waveform, R_fixture 50.000, V_fixture 2.500: 20-80 % time 226ps typ, 315ps min, 154ps max; typ from 1.74 V to 2.5 V
|   falling waveform, R_fixture 50.000, V_fixture 2.500: 20-80 % time 361ps typ, 397ps min, 339ps max; typ from 2.5 V to 1.74 V
|   falling waveform, R_fixture 50.000, V_fixture 0.0: 20-80 % time 206ps typ, 285ps min, 147ps max; typ from 0.696 V to 0 V
[Pulldown]
|Voltage   I(typ)   I(min)   I(max)
-2.5V     -2.991A    -2.35A     -4.091A
-1.132V   -472.6mA   -475.7mA   -480.1mA
-1.056V   -348.1mA   -381.3mA   -311.4mA
-980mV    -233mA     -290.9mA   -172.6mA
-904mV    -135.4mA   -206.7mA   -100.2mA
-828mV    -69.7mA    -132mA     -80.94mA
-752mV    -44.04mA   -71.78mA   -65.89mA
-676mV    -32.05mA   -32.21mA   -49.93mA
-524mV    -15.09mA   -9.266mA   -23.38mA
768mV     11.78mA    7.58mA     18.08mA
3.2V      20.83mA    16.52mA    26.8mA
5V        77.28mA    55.59mA    118mA
[Pullup]
|Voltage   I(typ)   I(min)   I(max)
-2.5V     91.33mA    65.8mA     149.4mA
-320mV    6.011mA    4.438mA    9.456mA
2.948V    -15.97mA   -14.48mA   -25.89mA
3.1V      -25.95mA   -55.2mA    -29.21mA
3.328V    -71.89mA   -262.4mA   -62.59mA
3.404V    -140.5mA   -351.2mA   -77.65mA
3.556V    -359.8mA   -541mA     -118.6mA
3.632V    -485.6mA   -639.6mA   -219.2mA
3.708V    -616.1mA   -739.9mA   -376.5mA
3.784V    -749.7mA   -841.4mA   -554.7mA
3.86V     -885.5mA   -943.8mA   -742.2mA
5V        -3.006A    -2.53A     -3.767A
[Ramp]
| variable   typ   min   max
dV/dt_r   0.417/0.370n   0.285/0.401n   0.695/0.328n
dV/dt_f   0.459/0.355n   0.303/0.392n   0.673/0.337n
R_load = 50.000
[Rising Waveform]
R_fixture= 50.000
V_fixture= 0.0
V_fixture_min= 0.0
V_fixture_max= 0.0
|time   V(typ)   V(min)   V(max)
0s        9.431nV    63.61nV    34.88nV
596ps     46.91uV    -244.9nV   -13.84mV
767ps     337.8uV    -244.9nV   581mV
960ps     -10.62mV   24.35uV    894.5mV
1.072ns   9.196mV    226.1uV    975.4mV
1.411ns   502mV      -1.9mV     1.091V
1.847ns   638.2mV    87.88mV    1.137V
2.224ns   670.6mV    372.2mV    1.15V
3.289ns   692.6mV    464.3mV    1.158V
20ns      695.7mV    475.1mV    1.159V
[Rising Waveform]
R_fixture= 50.000
V_fixture= 2.500
V_fixture_min= 2.380
V_fixture_max= 2.630
|time   V(typ)   V(min)   V(max)
0s        1.736V     1.876V     1.508V
528ps     1.736V     1.876V     1.514V
575ps     1.736V     1.876V     1.646V
711ps     1.737V     1.876V     2.325V
891ps     1.733V     1.876V     2.541V
1.163ns   2.29V      1.877V     2.597V
1.398ns   2.441V     1.866V     2.614V
1.881ns   2.483V     2.283V     2.626V
2.436ns   2.495V     2.365V     2.629V
20ns      2.5V       2.38V      2.63V
[Falling Waveform]
R_fixture= 50.000
V_fixture= 2.500
V_fixture_min= 2.380
V_fixture_max= 2.630
|time   V(typ)   V(min)   V(max)
0s        2.5V       2.38V      2.63V
612ps     2.5V       2.38V      2.651V
823ps     2.5V       2.38V      1.973V
1.093ns   2.52V      2.38V      1.687V
1.421ns   1.969V     2.38V      1.581V
1.916ns   1.792V     2.37V      1.528V
2.177ns   1.768V     2.085V     1.518V
2.359ns   1.758V     1.986V     1.515V
3.033ns   1.741V     1.898V     1.509V
20ns      1.736V     1.876V     1.508V
[Falling Waveform]
R_fixture= 50.000
V_fixture= 0.0
V_fixture_min= 0.0
V_fixture_max= 0.0
|time   V(typ)   V(min)   V(max)
0s        695.7mV    475.1mV    1.159V
568ps     695.7mV    475.1mV    1.146V
716ps     695.5mV    475.2mV    387.5mV
812ps     695.4mV    475.2mV    166.7mV
1.018ns   670.6mV    475.1mV    50.14mV
1.349ns   91.76mV    474.8mV    14.07mV
1.69ns    21.35mV    470.3mV    4.463mV
2.078ns   7.493mV    96.61mV    1.252mV
2.569ns   2.11mV     13.88mV    361uV
20ns      -263.3nV   114.3nV    15.9nV
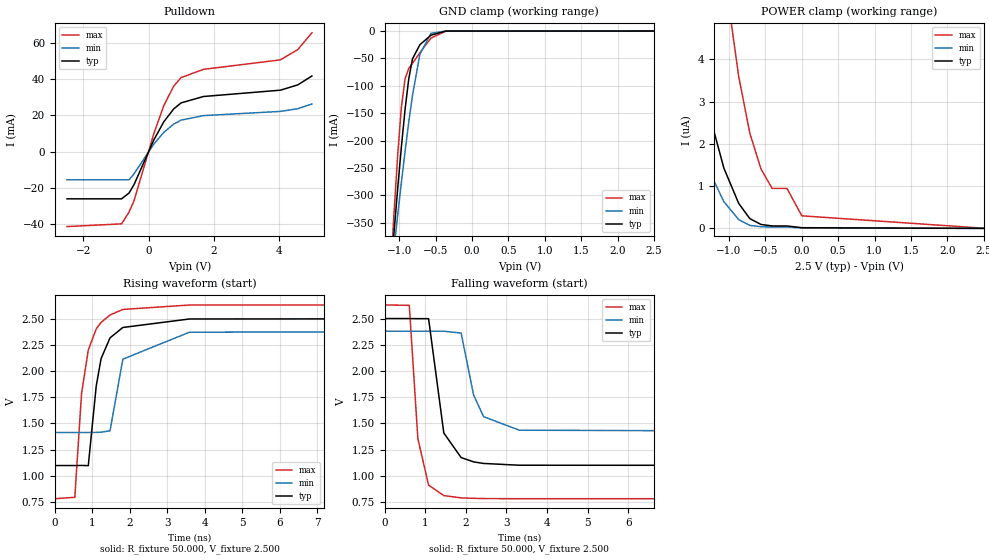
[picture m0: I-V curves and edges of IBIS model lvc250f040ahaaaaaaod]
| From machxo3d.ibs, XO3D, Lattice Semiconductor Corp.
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|   Model lvc250f040ahaaaaaaod
[Model] lvc250f040ahaaaaaaod
Model_type I/O_open_drain
Polarity   Non-Inverting
Enable   Active-Low
Vinl =  0.700V
Vinh =  1.700V
Vmeas =  1.250V
Cref =  0.0F
Rref = 10.00k
Vref = 2.50V
C_comp   4.200pF   3.800pF   7.500pF
[Temperature Range]   25.000   0.105k   -40.000
[Voltage Range]   2.500V   2.380V   2.630V
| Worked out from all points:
|   slope of the pulldown table from 0 to 0.375 V, typ, clamps not added: 27.2 ohm
|   GND clamp passes 1 mA (typ) near -0.43 V on its own axis
|   rising waveform, R_fixture 50.000, V_fixture 2.500: 20-80 % time 337ps typ, 341ps min, 339ps max; typ from 1.1 V to 2.5 V
|   falling waveform, R_fixture 50.000, V_fixture 2.500: 20-80 % time 314ps typ, 382ps min, 219ps max; typ from 2.5 V to 1.1 V
[Pulldown]
|Voltage   I(typ)   I(min)   I(max)
-2.5V     -26.15mA   -15.63mA   -41.49mA
-828mV    -26.15mA   -15.63mA   -39.97mA
-600mV    -22.93mA   -15.63mA   -33.47mA
-448mV    -18.28mA   -12.33mA   -27.2mA
160mV     6.444mA    4.153mA    9.94mA
464mV     16.44mA    10.59mA    25.34mA
768mV     23.56mA    15.16mA    36.16mA
996mV     26.9mA     17.37mA    40.9mA
1.68V     30.42mA    19.86mA    45.43mA
4.036V    33.91mA    22.18mA    50.67mA
4.568V    36.84mA    23.68mA    56.35mA
5V        41.77mA    26.28mA    65.62mA
[GND_clamp]
|Voltage   I(typ)   I(min)   I(max)
-2.5V     -2.99A     -2.35A     -4.091A
-1.123V   -455.1mA   -463.2mA   -453.6mA
-1.072V   -370.5mA   -399.5mA   -336.3mA
-1.021V   -289.1mA   -337.4mA   -228.5mA
-970mV    -212.6mA   -277.3mA   -139.9mA
-919mV    -143.6mA   -220.1mA   -87.34mA
-868mV    -87.35mA   -166.5mA   -68.39mA
-817mV    -50.9mA    -117.8mA   -59.07mA
-715mV    -24.94mA   -42.34mA   -39.63mA
-562mV    -7.547mA   -4.077mA   -12.85mA
-358mV    -114uA     -53.77uA   -172.8uA
2.5V      0A         0A         0A
[POWER_clamp]
|Voltage   I(typ)   I(min)   I(max)
-2.5V     16.57uA    10.06uA    44.17uA
-2.09V    10.8uA     6.285uA    30.12uA
-1.682V   6.109uA    3.358uA    18.45uA
-1.376V   3.384uA    1.736uA    11.44uA
-1.07V    1.428uA    632.8nA    6.128uA
-866mV    590.6nA    207.8nA    3.594uA
-713mV    230.3nA    70.46nA    2.252uA
-560mV    93.24nA    38.97nA    1.406uA
-407mV    57.67nA    33.36nA    946nA
-203mV    57.67nA    32.35nA    946nA
1mV       16.06nA    10.58nA    297.5nA
2.5V      0A         0A         3.667nA
[Ramp]
| variable   typ   min   max
dV/dt_r   0.841/0.337n   0.579/0.342n   1.108/0.339n
dV/dt_f   0.841/0.310n   0.579/0.379n   1.108/0.218n
R_load = 50.000
[Rising Waveform]
R_fixture= 50.000
V_fixture= 2.500
V_fixture_min= 2.380
V_fixture_max= 2.630
|time   V(typ)   V(min)   V(max)
0s        1.099V     1.414V     783mV
534ps     1.099V     1.414V     796.1mV
713ps     1.1V       1.414V     1.784V
893ps     1.098V     1.414V     2.2V
1.104ns   1.856V     1.415V     2.401V
1.234ns   2.118V     1.417V     2.463V
1.472ns   2.316V     1.43V      2.534V
1.814ns   2.415V     2.113V     2.587V
3.589ns   2.496V     2.37V      2.629V
20ns      2.5V       2.38V      2.63V
[Falling Waveform]
R_fixture= 50.000
V_fixture= 2.500
V_fixture_min= 2.380
V_fixture_max= 2.630
|time   V(typ)   V(min)   V(max)
0s        2.5V       2.38V      2.63V
608ps     2.5V       2.38V      2.626V
819ps     2.499V     2.38V      1.356V
1.083ns   2.499V     2.38V      912.3mV
1.458ns   1.409V     2.379V     812.6mV
1.884ns   1.175V     2.362V     790.7mV
2.191ns   1.134V     1.772V     786.5mV
2.436ns   1.119V     1.565V     784.2mV
3.315ns   1.102V     1.436V     783mV
20ns      1.099V     1.414V     783mV
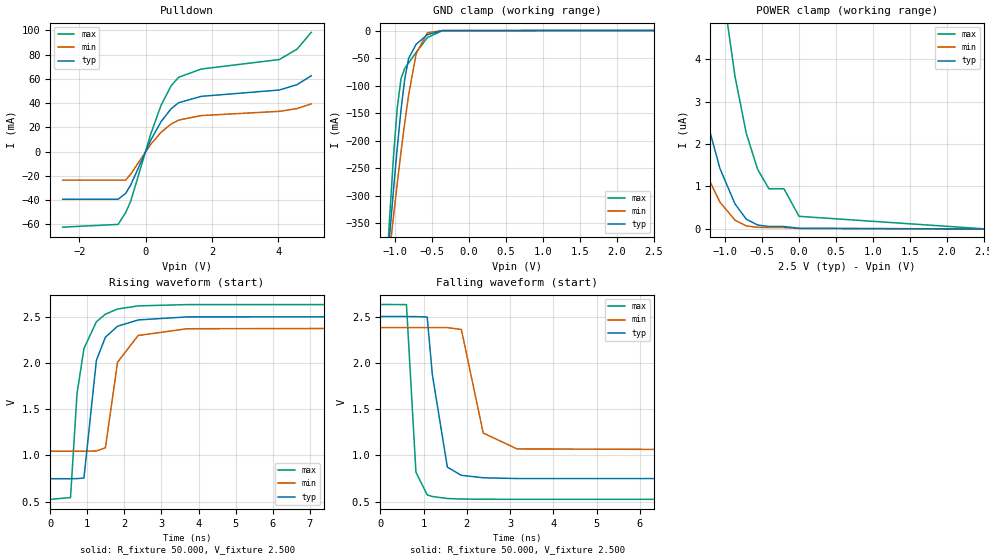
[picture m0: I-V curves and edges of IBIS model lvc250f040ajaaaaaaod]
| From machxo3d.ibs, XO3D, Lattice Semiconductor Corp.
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|   Model lvc250f040ajaaaaaaod
[Model] lvc250f040ajaaaaaaod
Model_type I/O_open_drain
Polarity   Non-Inverting
Enable   Active-Low
Vinl =  0.700V
Vinh =  1.700V
Vmeas =  1.250V
Cref =  0.0F
Rref = 10.00k
Vref = 2.50V
C_comp   4.200pF   3.800pF   7.500pF
[Temperature Range]   25.000   0.105k   -40.000
[Voltage Range]   2.500V   2.380V   2.630V
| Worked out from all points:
|   slope of the pulldown table from 0 to 0.375 V, typ, clamps not added: 18.1 ohm
|   GND clamp passes 1 mA (typ) near -0.43 V on its own axis
|   rising waveform, R_fixture 50.000, V_fixture 2.500: 20-80 % time 334ps typ, 339ps min, 338ps max; typ from 0.747 V to 2.5 V
|   falling waveform, R_fixture 50.000, V_fixture 2.500: 20-80 % time 223ps typ, 334ps min, 138ps max; typ from 2.5 V to 0.747 V
[Pulldown]
|Voltage   I(typ)   I(min)   I(max)
-2.5V     -39.23mA   -23.44mA   -62.24mA
-828mV    -39.23mA   -23.44mA   -59.96mA
-600mV    -34.4mA    -23.44mA   -50.2mA
-448mV    -27.42mA   -18.49mA   -40.8mA
160mV     9.666mA    6.229mA    14.91mA
464mV     24.66mA    15.88mA    38.02mA
768mV     35.33mA    22.74mA    54.24mA
996mV     40.36mA    26.05mA    61.35mA
1.68V     45.63mA    29.79mA    68.15mA
4.036V    50.87mA    33.27mA    76.01mA
4.568V    55.25mA    35.53mA    84.53mA
5V        62.66mA    39.42mA    98.43mA
[GND_clamp]
|Voltage   I(typ)   I(min)   I(max)
-2.5V     -2.99A     -2.35A     -4.091A
-1.123V   -455.1mA   -463.2mA   -453.6mA
-1.072V   -370.5mA   -399.5mA   -336.3mA
-1.021V   -289.1mA   -337.4mA   -228.5mA
-970mV    -212.6mA   -277.3mA   -139.9mA
-919mV    -143.6mA   -220.1mA   -87.34mA
-868mV    -87.35mA   -166.5mA   -68.39mA
-817mV    -50.9mA    -117.8mA   -59.07mA
-715mV    -24.94mA   -42.34mA   -39.63mA
-562mV    -7.547mA   -4.077mA   -12.85mA
-358mV    -114uA     -53.77uA   -172.8uA
2.5V      0A         0A         0A
[POWER_clamp]
|Voltage   I(typ)   I(min)   I(max)
-2.5V     16.57uA    10.06uA    44.17uA
-2.09V    10.8uA     6.285uA    30.12uA
-1.682V   6.109uA    3.358uA    18.45uA
-1.376V   3.384uA    1.736uA    11.44uA
-1.07V    1.428uA    632.8nA    6.128uA
-866mV    590.6nA    207.8nA    3.594uA
-713mV    230.3nA    70.46nA    2.252uA
-560mV    93.25nA    38.97nA    1.406uA
-407mV    57.68nA    33.35nA    946nA
-203mV    57.68nA    32.34nA    946nA
1mV       16.06nA    10.58nA    297.5nA
2.5V      0A         0A         3.667nA
[Ramp]
| variable   typ   min   max
dV/dt_r   1.052/0.334n   0.801/0.337n   1.263/0.338n
dV/dt_f   1.052/0.221n   0.801/0.333n   1.263/0.137n
R_load = 50.000
[Rising Waveform]
R_fixture= 50.000
V_fixture= 2.500
V_fixture_min= 2.380
V_fixture_max= 2.630
|time   V(typ)   V(min)   V(max)
0s        747.2mV    1.044V     524.3mV
546ps     747.2mV    1.044V     542.9mV
721ps     747.9mV    1.044V     1.665V
908ps     754.4mV    1.044V     2.154V
1.244ns   2.026V     1.047V     2.443V
1.487ns   2.277V     1.081V     2.526V
1.815ns   2.395V     2.006V     2.581V
2.37ns    2.463V     2.295V     2.615V
3.689ns   2.496V     2.368V     2.629V
20ns      2.5V       2.38V      2.63V
[Falling Waveform]
R_fixture= 50.000
V_fixture= 2.500
V_fixture_min= 2.380
V_fixture_max= 2.630
|time   V(typ)   V(min)   V(max)
0s        2.5V       2.38V      2.63V
605ps     2.5V       2.38V      2.629V
824ps     2.499V     2.38V      818.2mV
1.084ns   2.495V     2.38V      572.6mV
1.203ns   1.873V     2.38V      554.7mV
1.55ns    872.5mV    2.38V      533.3mV
1.874ns   783.7mV    2.36V      527.3mV
2.379ns   757.3mV    1.241V     524.9mV
3.16ns    748.9mV    1.069V     524.4mV
20ns      747.1mV    1.044V     524.3mV
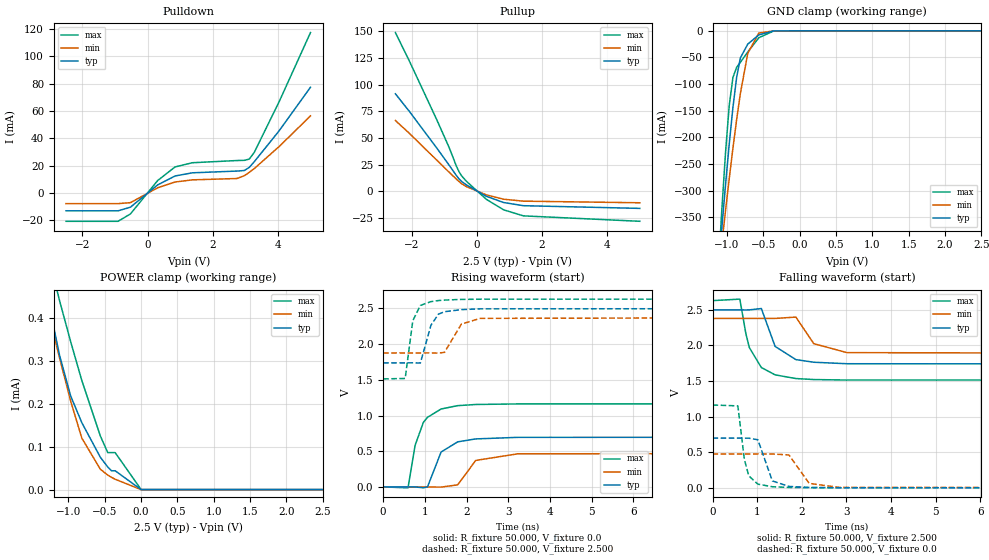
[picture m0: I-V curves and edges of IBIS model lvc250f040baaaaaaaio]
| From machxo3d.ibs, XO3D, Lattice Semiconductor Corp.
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|   Model lvc250f040baaaaaaaio
[Model] lvc250f040baaaaaaaio
Model_type I/O
Polarity   Non-Inverting
Enable   Active-Low
Vinl =  0.700V
Vinh =  1.700V
Vmeas =  1.250V
Cref =  0.0F
Rref =  1.000M
Vref =  0.0V
C_comp   4.200pF   3.800pF   7.500pF
[Temperature Range]   25.000   0.105k   -40.000
[Voltage Range]   2.500V   2.380V   2.630V
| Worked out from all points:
|   slope of the pulldown table from 0 to 0.375 V, typ, clamps not added: 54.4 ohm
|   slope of the pullup table from 0 to 0.375 V, typ, clamps not added: 65.1 ohm
|   GND clamp passes 1 mA (typ) near -0.43 V on its own axis
|   POWER clamp passes 1 mA (typ) near -1.90 V on its own axis
|   rising waveform, R_fixture 50.000, V_fixture 0.0: 20-80 % time 369ps typ, 403ps min, 328ps max; typ from 0.002 V to 0.7 V
|   rising waveform, R_fixture 50.000, V_fixture 2.500: 20-80 % time 227ps typ, 315ps min, 154ps max; typ from 1.74 V to 2.5 V
|   falling waveform, R_fixture 50.000, V_fixture 2.500: 20-80 % time 361ps typ, 397ps min, 338ps max; typ from 2.5 V to 1.74 V
|   falling waveform, R_fixture 50.000, V_fixture 0.0: 20-80 % time 205ps typ, 288ps min, 148ps max; typ from 0.7 V to 0.002 V
[Pulldown]
|Voltage   I(typ)   I(min)   I(max)
-2.5V     -13.08mA   -7.815mA   -20.75mA
-904mV    -13.08mA   -7.815mA   -20.75mA
-524mV    -10.41mA   -7.109mA   -15.34mA
312mV     5.902mA    3.803mA    9.102mA
844mV     12.43mA    8.006mA    19.04mA
1.376V    14.74mA    9.586mA    22.12mA
2.744V    16.02mA    10.57mA    23.73mA
2.972V    16.42mA    12.64mA    23.88mA
3.124V    18.76mA    15.12mA    24.81mA
3.276V    22.89mA    17.87mA    29.77mA
4.036V    45.45mA    33.93mA    66.69mA
5V        77.39mA    56.41mA    117.4mA
[Pullup]
|Voltage   I(typ)   I(min)   I(max)
-2.5V     91.47mA    66.45mA    148.9mA
-2.068V   74.85mA    54.31mA    122mA
-1.232V   40.67mA    29.31mA    67.26mA
-852mV    24.62mA    17.98mA    41.17mA
-624mV    14.67mA    11.34mA    23.35mA
-548mV    11.68mA    9.226mA    18.47mA
-472mV    9.383mA    7.274mA    14.7mA
-320mV    5.997mA    4.418mA    9.439mA
288mV     -4.573mA   -3.272mA   -7.415mA
820mV     -10.47mA   -7.36mA    -17.31mA
1.428V    -13.44mA   -9.183mA   -22.98mA
5V        -15.96mA   -10.7mA    -28.07mA
[GND_clamp]
|Voltage   I(typ)   I(min)   I(max)
-2.5V     -2.99A     -2.35A     -4.091A
-1.123V   -455.1mA   -463.2mA   -453.7mA
-1.072V   -370.5mA   -399.5mA   -336.3mA
-1.021V   -289.2mA   -337.4mA   -228.6mA
-970mV    -212.6mA   -277.4mA   -140mA
-919mV    -143.6mA   -220.1mA   -87.39mA
-868mV    -87.38mA   -166.5mA   -68.44mA
-817mV    -50.93mA   -117.8mA   -59.12mA
-715mV    -24.98mA   -42.36mA   -39.69mA
-562mV    -7.596mA   -4.111mA   -12.93mA
-358mV    -193.4uA   -101.2uA   -309.3uA
2.5V      13.17nA    0A         -19.29uA
[POWER_clamp]
|Voltage   I(typ)   I(min)   I(max)
-2.5V     1.538mA    1.365mA    2.125mA
-1.325V   482.6uA    450.2uA    591.5uA
-1.274V   438.4uA    413.8uA    546.6uA
-1.121V   313.5uA    307.1uA    441uA
-968mV    218.6uA    206.5uA    345.2uA
-815mV    156.3uA    120.3uA    254.8uA
-560mV    75.6uA     47.55uA    125.2uA
-458mV    52.75uA    33.88uA    86.35uA
-407mV    44.01uA    28.68uA    86.35uA
-356mV    44.01uA    24.21uA    86.35uA
1mV       0A         0A         141nA
2.5V      0A         0A         0A
[Ramp]
| variable   typ   min   max
dV/dt_r   0.419/0.369n   0.286/0.401n   0.697/0.327n
dV/dt_f   0.457/0.355n   0.302/0.393n   0.670/0.336n
R_load = 50.000
[Rising Waveform]
R_fixture= 50.000
V_fixture= 0.0
V_fixture_min= 0.0
V_fixture_max= 0.0
|time   V(typ)   V(min)   V(max)
0s        2.016mV    1.415mV    2.955mV
596ps     2.067mV    1.417mV    -10.34mV
767ps     2.318mV    1.417mV    586.8mV
965ps     -9.194mV   1.441mV    905.5mV
1.064ns   4.222mV    1.644mV    976.9mV
1.39ns    490.9mV    23.88uV    1.093V
1.789ns   633.8mV    31.71mV    1.14V
2.221ns   674.4mV    373.5mV    1.156V
3.226ns   696.2mV    465.6mV    1.164V
20ns      699.6mV    477.4mV    1.165V
[Rising Waveform]
R_fixture= 50.000
V_fixture= 2.500
V_fixture_min= 2.380
V_fixture_max= 2.630
|time   V(typ)   V(min)   V(max)
0s        1.738V     1.877V     1.514V
528ps     1.738V     1.877V     1.52V
711ps     1.739V     1.877V     2.328V
893ps     1.736V     1.877V     2.542V
1.146ns   2.264V     1.878V     2.595V
1.325ns   2.419V     1.874V     2.61V
1.472ns   2.454V     1.886V     2.617V
1.877ns   2.483V     2.281V     2.626V
2.328ns   2.494V     2.361V     2.629V
20ns      2.5V       2.38V      2.63V
[Falling Waveform]
R_fixture= 50.000
V_fixture= 2.500
V_fixture_min= 2.380
V_fixture_max= 2.630
|time   V(typ)   V(min)   V(max)
0s        2.5V       2.38V      2.63V
612ps     2.5V       2.38V      2.651V
749ps     2.499V     2.38V      2.161V
825ps     2.5V       2.38V      1.971V
1.094ns   2.519V     2.38V      1.691V
1.403ns   1.987V     2.38V      1.588V
1.868ns   1.802V     2.399V     1.536V
2.269ns   1.765V     2.026V     1.522V
3.013ns   1.744V     1.9V       1.515V
20ns      1.738V     1.877V     1.514V
[Falling Waveform]
R_fixture= 50.000
V_fixture= 0.0
V_fixture_min= 0.0
V_fixture_max= 0.0
|time   V(typ)   V(min)   V(max)
0s        699.6mV    477.4mV    1.165V
568ps     699.6mV    477.3mV    1.152V
714ps     699.4mV    477.5mV    400.8mV
812ps     699.3mV    477.5mV    170.8mV
1.016ns   676.8mV    477.5mV    53.32mV
1.341ns   98.78mV    477mV      17.37mV
1.713ns   21.21mV    463.1mV    7.132mV
2.167ns   7.611mV    63.7mV     4.1mV
2.836ns   3.179mV    8.651mV    3.145mV
20ns      2.016mV    1.415mV    2.955mV
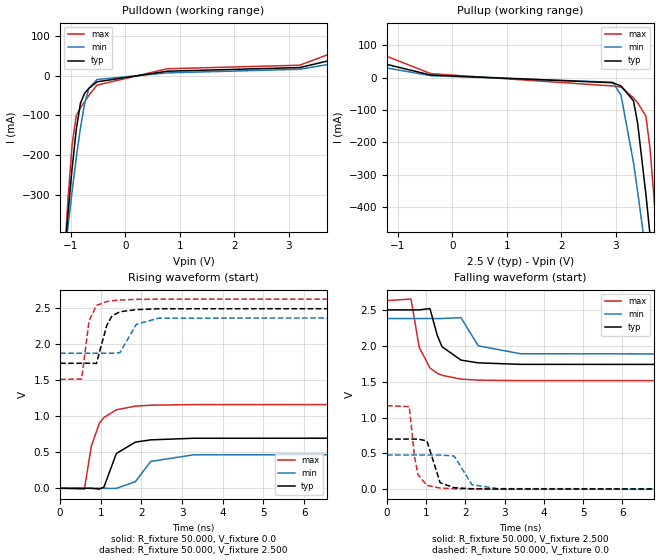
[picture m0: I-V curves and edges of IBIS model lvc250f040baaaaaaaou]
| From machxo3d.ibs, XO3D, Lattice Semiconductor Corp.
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|   Model lvc250f040baaaaaaaou
[Model] lvc250f040baaaaaaaou
Model_type Output
Polarity   Non-Inverting
Enable   Active-High
Vmeas =  1.250V
Cref =  0.0F
Rref =  1.000M
Vref =  0.0V
C_comp   4.200pF   3.800pF   7.500pF
[Temperature Range]   25.000   0.105k   -40.000
[Voltage Range]   2.500V   2.380V   2.630V
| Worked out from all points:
|   slope of the pulldown table from 0 to 0.375 V, typ, clamps not added: 54.3 ohm
|   slope of the pullup table from 0 to 0.375 V, typ, clamps not added: 64.7 ohm
|   rising waveform, R_fixture 50.000, V_fixture 0.0: 20-80 % time 366ps typ, 402ps min, 328ps max; typ from 0.002 V to 0.7 V
|   rising waveform, R_fixture 50.000, V_fixture 2.500: 20-80 % time 227ps typ, 314ps min, 154ps max; typ from 1.74 V to 2.5 V
|   falling waveform, R_fixture 50.000, V_fixture 2.500: 20-80 % time 360ps typ, 385ps min, 337ps max; typ from 2.5 V to 1.74 V
|   falling waveform, R_fixture 50.000, V_fixture 0.0: 20-80 % time 207ps typ, 287ps min, 147ps max; typ from 0.7 V to 0.002 V
[Pulldown]
|Voltage   I(typ)   I(min)   I(max)
-2.5V     -2.991A    -2.35A     -4.091A
-1.132V   -472.6mA   -475.7mA   -480.1mA
-1.056V   -348.1mA   -381.3mA   -311.4mA
-980mV    -233.1mA   -290.9mA   -172.6mA
-904mV    -135.4mA   -206.7mA   -100.3mA
-828mV    -69.73mA   -132.1mA   -80.99mA
-752mV    -44.08mA   -71.8mA    -65.95mA
-676mV    -32.09mA   -32.23mA   -50mA
-524mV    -15.14mA   -9.304mA   -23.47mA
768mV     11.7mA     7.532mA    17.93mA
3.2V      20.89mA    16.59mA    26.85mA
5V        78.92mA    57.89mA    119.3mA
[Pullup]
|Voltage   I(typ)   I(min)   I(max)
-2.5V     93.01mA    67.81mA    151mA
-396mV    7.635mA    5.714mA    11.96mA
2.948V    -16.03mA   -14.51mA   -26.03mA
3.1V      -25.99mA   -55.21mA   -29.31mA
3.328V    -71.92mA   -262.4mA   -62.64mA
3.404V    -140.6mA   -351.2mA   -77.7mA
3.556V    -359.8mA   -541mA     -118.7mA
3.632V    -485.6mA   -639.6mA   -219.2mA
3.708V    -616.1mA   -739.9mA   -376.5mA
3.784V    -749.8mA   -841.4mA   -554.7mA
3.86V     -885.5mA   -943.8mA   -742.2mA
5V        -3.006A    -2.53A     -3.767A
[Ramp]
| variable   typ   min   max
dV/dt_r   0.419/0.369n   0.286/0.401n   0.697/0.327n
dV/dt_f   0.457/0.355n   0.302/0.393n   0.670/0.336n
R_load = 50.000
[Rising Waveform]
R_fixture= 50.000
V_fixture= 0.0
V_fixture_min= 0.0
V_fixture_max= 0.0
|time   V(typ)   V(min)   V(max)
0s        2.016mV    1.415mV    2.955mV
596ps     2.063mV    1.413mV    -10.34mV
767ps     2.313mV    1.413mV    586.8mV
965ps     -9.187mV   1.506mV    905.5mV
1.078ns   19.66mV    1.641mV    985.2mV
1.382ns   484.9mV    345uV      1.092V
1.851ns   643.1mV    93.42mV    1.143V
2.226ns   674.4mV    375.1mV    1.156V
3.28ns    696.6mV    466.6mV    1.164V
20ns      699.6mV    477.4mV    1.165V
[Rising Waveform]
R_fixture= 50.000
V_fixture= 2.500
V_fixture_min= 2.380
V_fixture_max= 2.630
|time   V(typ)   V(min)   V(max)
0s        1.738V     1.877V     1.514V
528ps     1.738V     1.877V     1.52V
711ps     1.739V     1.877V     2.328V
893ps     1.736V     1.877V     2.542V
1.146ns   2.264V     1.878V     2.595V
1.276ns   2.397V     1.877V     2.607V
1.472ns   2.454V     1.886V     2.617V
1.873ns   2.483V     2.279V     2.626V
2.419ns   2.495V     2.364V     2.629V
20ns      2.5V       2.38V      2.63V
[Falling Waveform]
R_fixture= 50.000
V_fixture= 2.500
V_fixture_min= 2.380
V_fixture_max= 2.630
|time   V(typ)   V(min)   V(max)
0s        2.5V       2.38V      2.63V
612ps     2.5V       2.38V      2.651V
821ps     2.5V       2.38V      1.979V
1.094ns   2.519V     2.38V      1.691V
1.283ns   2.143V     2.379V     1.616V
1.403ns   1.987V     2.38V      1.588V
1.888ns   1.8V       2.391V     1.535V
2.325ns   1.762V     2V         1.521V
3.402ns   1.741V     1.889V     1.514V
20ns      1.738V     1.877V     1.514V
[Falling Waveform]
R_fixture= 50.000
V_fixture= 0.0
V_fixture_min= 0.0
V_fixture_max= 0.0
|time   V(typ)   V(min)   V(max)
0s        699.6mV    477.4mV    1.165V
568ps     699.6mV    477.3mV    1.152V
701ps     699.4mV    477.3mV    455.7mV
790ps     699.2mV    477.5mV    202.6mV
1.018ns   674.6mV    477.5mV    53.33mV
1.355ns   91.07mV    477.1mV    17.04mV
1.713ns   21.23mV    463.1mV    7.443mV
2.167ns   7.638mV    63.68mV    4.042mV
2.838ns   3.146mV    8.661mV    3.145mV
20ns      2.016mV    1.415mV    2.955mV
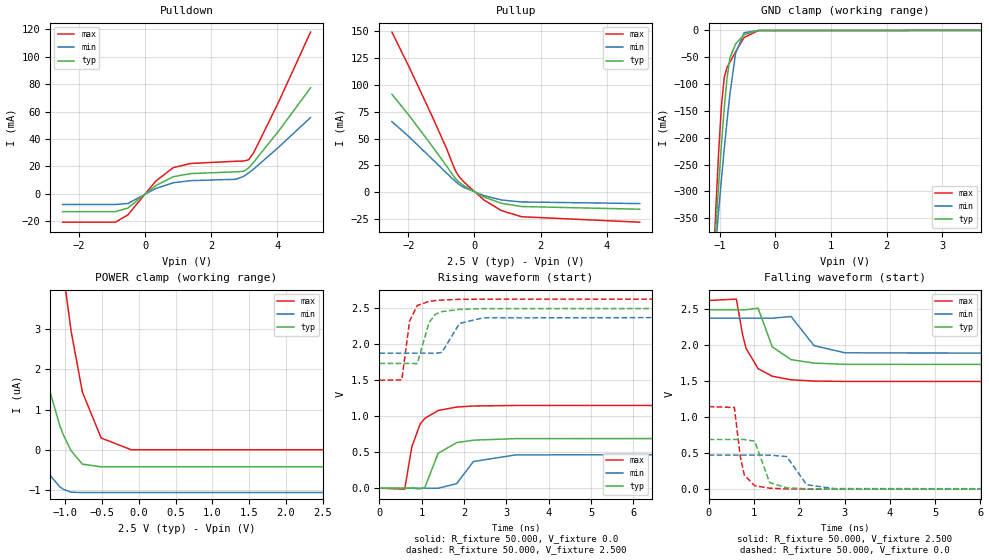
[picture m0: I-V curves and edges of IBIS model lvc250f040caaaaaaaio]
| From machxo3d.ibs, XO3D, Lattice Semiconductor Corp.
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|   Model lvc250f040caaaaaaaio
[Model] lvc250f040caaaaaaaio
Model_type I/O
Polarity   Non-Inverting
Enable   Active-Low
Vinl =  0.700V
Vinh =  1.700V
Vmeas =  1.250V
Cref =  0.0F
Rref =  1.000M
Vref =  0.0V
C_comp   4.200pF   3.800pF   7.500pF
[Temperature Range]   25.000   0.105k   -40.000
[Voltage Range]   2.500V   2.380V   2.630V
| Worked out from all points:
|   slope of the pulldown table from 0 to 0.375 V, typ, clamps not added: 54.4 ohm
|   slope of the pullup table from 0 to 0.375 V, typ, clamps not added: 65.1 ohm
|   GND clamp passes 1 mA (typ) near -0.43 V on its own axis
|   rising waveform, R_fixture 50.000, V_fixture 0.0: 20-80 % time 363ps typ, 399ps min, 327ps max; typ from 0 V to 0.691 V
|   rising waveform, R_fixture 50.000, V_fixture 2.500: 20-80 % time 227ps typ, 317ps min, 155ps max; typ from 1.73 V to 2.5 V
|   falling waveform, R_fixture 50.000, V_fixture 2.500: 20-80 % time 358ps typ, 381ps min, 339ps max; typ from 2.5 V to 1.73 V
|   falling waveform, R_fixture 50.000, V_fixture 0.0: 20-80 % time 205ps typ, 286ps min, 145ps max; typ from 0.691 V to 0 V
[Pulldown]
|Voltage   I(typ)   I(min)   I(max)
-2.5V     -13.08mA   -7.815mA   -20.75mA
-904mV    -13.08mA   -7.815mA   -20.75mA
-524mV    -10.41mA   -7.109mA   -15.34mA
312mV     5.902mA    3.803mA    9.102mA
844mV     12.43mA    8.006mA    19.04mA
1.376V    14.74mA    9.586mA    22.12mA
2.744V    16.02mA    10.57mA    23.73mA
2.972V    16.41mA    12.64mA    23.88mA
3.124V    18.78mA    15.15mA    24.77mA
3.276V    22.93mA    17.94mA    29.79mA
4.036V    45.78mA    34.01mA    67.04mA
5V        77.33mA    55.63mA    118mA
[Pullup]
|Voltage   I(typ)   I(min)   I(max)
-2.5V     91.38mA    65.84mA    149.4mA
-1.992V   72.11mA    52.01mA    117.8mA
-1.308V   44.07mA    31.73mA    72.61mA
-852mV    24.68mA    18.03mA    41.27mA
-624mV    14.69mA    11.35mA    23.35mA
-548mV    11.68mA    9.231mA    18.44mA
-472mV    9.375mA    7.275mA    14.66mA
-320mV    5.997mA    4.418mA    9.438mA
288mV     -4.573mA   -3.272mA   -7.415mA
820mV     -10.47mA   -7.36mA    -17.31mA
1.428V    -13.44mA   -9.183mA   -22.98mA
5V        -15.96mA   -10.7mA    -28.07mA
[GND_clamp]
|Voltage   I(typ)   I(min)   I(max)
-2.5V     -2.99A     -2.35A     -4.091A
-1.123V   -455.1mA   -463.2mA   -453.7mA
-1.072V   -370.5mA   -399.5mA   -336.3mA
-1.021V   -289.2mA   -337.4mA   -228.6mA
-970mV    -212.6mA   -277.4mA   -140mA
-919mV    -143.6mA   -220.1mA   -87.4mA
-868mV    -87.39mA   -166.5mA   -68.45mA
-817mV    -50.94mA   -117.8mA   -59.13mA
-715mV    -24.99mA   -42.37mA   -39.7mA
-562mV    -7.608mA   -4.125mA   -12.95mA
-307mV    -97.66uA   -51.76uA   -173.8uA
5V        114uA      49.34uA    266.8uA
[POWER_clamp]
|Voltage   I(typ)   I(min)   I(max)
-2.5V     22.27uA    8.76uA     64.97uA
-2.141V   14.03uA    4.838uA    43.67uA
-1.835V   8.45uA     2.288uA    28.47uA
-1.58V    4.901uA    735.9nA    18.31uA
-1.274V   1.887uA    -485.7nA   9.321uA
-1.07V    594.4nA    -923.9nA   5.173uA
-1.019V   355.1nA    -987.6nA   4.351uA
-917mV    -26.38nA   -1.058uA   2.951uA
-764mV    -358.6nA   -1.065uA   1.434uA
-509mV    -424.7nA   -1.065uA   291.6nA
-101mV    -424.7nA   -1.065uA   0A
2.5V      -424.7nA   -1.065uA   0A
[Ramp]
| variable   typ   min   max
dV/dt_r   0.415/0.367n   0.284/0.400n   0.689/0.327n
dV/dt_f   0.460/0.355n   0.303/0.392n   0.677/0.336n
R_load = 50.000
[Rising Waveform]
R_fixture= 50.000
V_fixture= 0.0
V_fixture_min= 0.0
V_fixture_max= 0.0
|time   V(typ)   V(min)   V(max)
0s        9.102nV    62.88nV    33.47nV
596ps     26.07uV    3.653uV    -13.81mV
766ps     322.9uV    3.653uV    576.9mV
964ps     -11.15mV   27.88uV    892.4mV
1.072ns   9.24mV     239uV      968.7mV
1.387ns   483.5mV    -1.092mV   1.078V
1.824ns   632.1mV    63.33mV    1.126V
2.221ns   666.2mV    370.5mV    1.141V
3.222ns   687.9mV    461.8mV    1.148V
20ns      691.3mV    473.6mV    1.149V
[Rising Waveform]
R_fixture= 50.000
V_fixture= 2.500
V_fixture_min= 2.380
V_fixture_max= 2.630
|time   V(typ)   V(min)   V(max)
0s        1.731V     1.874V     1.497V
528ps     1.731V     1.874V     1.503V
712ps     1.732V     1.874V     2.319V
894ps     1.729V     1.874V     2.536V
1.17ns    2.296V     1.875V     2.592V
1.319ns   2.414V     1.871V     2.604V
1.476ns   2.451V     1.885V     2.611V
1.893ns   2.482V     2.287V     2.621V
2.444ns   2.492V     2.364V     2.624V
20ns      2.497V     2.379V     2.625V
[Falling Waveform]
R_fixture= 50.000
V_fixture= 2.500
V_fixture_min= 2.380
V_fixture_max= 2.630
|time   V(typ)   V(min)   V(max)
0s        2.497V     2.379V     2.625V
612ps     2.497V     2.379V     2.645V
749ps     2.496V     2.379V     2.151V
825ps     2.497V     2.379V     1.96V
1.091ns   2.518V     2.379V     1.677V
1.403ns   1.981V     2.379V     1.572V
1.819ns   1.802V     2.402V     1.522V
2.327ns   1.754V     1.997V     1.504V
3.009ns   1.737V     1.897V     1.499V
20ns      1.731V     1.874V     1.497V
[Falling Waveform]
R_fixture= 50.000
V_fixture= 0.0
V_fixture_min= 0.0
V_fixture_max= 0.0
|time   V(typ)   V(min)   V(max)
0s        691.3mV    473.6mV    1.149V
568ps     691.3mV    473.5mV    1.136V
700ps     691.2mV    473.5mV    446.5mV
789ps     690.8mV    473.7mV    194.2mV
1.018ns   666.3mV    473.7mV    47.45mV
1.345ns   92mV       473.3mV    13.62mV
1.722ns   18.12mV    454.1mV    3.769mV
2.165ns   5.451mV    61.95mV    939.8uV
2.77ns    1.329mV    8.238mV    216.4uV
20ns      1.918nV    -61.27nV   -105.9nV
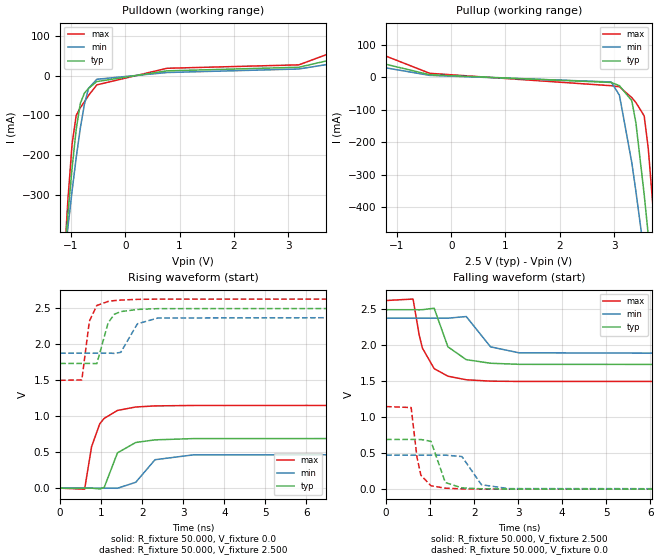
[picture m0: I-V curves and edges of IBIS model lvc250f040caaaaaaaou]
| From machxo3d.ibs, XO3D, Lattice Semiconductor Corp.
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|   Model lvc250f040caaaaaaaou
[Model] lvc250f040caaaaaaaou
Model_type Output
Polarity   Non-Inverting
Enable   Active-High
Vmeas =  1.250V
Cref =  0.0F
Rref =  1.000M
Vref =  0.0V
C_comp   4.200pF   3.800pF   7.500pF
[Temperature Range]   25.000   0.105k   -40.000
[Voltage Range]   2.500V   2.380V   2.630V
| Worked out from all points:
|   slope of the pulldown table from 0 to 0.375 V, typ, clamps not added: 53.8 ohm
|   slope of the pullup table from 0 to 0.375 V, typ, clamps not added: 65.1 ohm
|   rising waveform, R_fixture 50.000, V_fixture 0.0: 20-80 % time 364ps typ, 400ps min, 327ps max; typ from 0 V to 0.691 V
|   rising waveform, R_fixture 50.000, V_fixture 2.500: 20-80 % time 227ps typ, 315ps min, 155ps max; typ from 1.73 V to 2.5 V
|   falling waveform, R_fixture 50.000, V_fixture 2.500: 20-80 % time 359ps typ, 376ps min, 339ps max; typ from 2.5 V to 1.73 V
|   falling waveform, R_fixture 50.000, V_fixture 0.0: 20-80 % time 205ps typ, 286ps min, 145ps max; typ from 0.691 V to 0 V
[Pulldown]
|Voltage   I(typ)   I(min)   I(max)
-2.5V     -2.991A    -2.35A     -4.091A
-1.132V   -472.7mA   -475.7mA   -480.1mA
-1.056V   -348.1mA   -381.3mA   -311.4mA
-980mV    -233.1mA   -290.9mA   -172.7mA
-904mV    -135.4mA   -206.7mA   -100.3mA
-828mV    -69.74mA   -132.1mA   -81mA
-752mV    -44.09mA   -71.81mA   -65.96mA
-676mV    -32.1mA    -32.24mA   -50.01mA
-524mV    -15.15mA   -9.318mA   -23.48mA
768mV     11.87mA    7.615mA    18.3mA
3.2V      20.91mA    16.55mA    26.95mA
5V        77.46mA    55.68mA    118.3mA
[Pullup]
|Voltage   I(typ)   I(min)   I(max)
-2.5V     91.52mA    65.89mA    149.8mA
-396mV    7.693mA    5.726mA    12.11mA
2.948V    -16.04mA   -14.52mA   -26.02mA
3.1V      -26mA      -55.22mA   -29.32mA
3.328V    -71.93mA   -262.4mA   -62.65mA
3.404V    -140.6mA   -351.2mA   -77.71mA
3.556V    -359.8mA   -541mA     -118.7mA
3.632V    -485.6mA   -639.6mA   -219.2mA
3.708V    -616.1mA   -739.9mA   -376.5mA
3.784V    -749.8mA   -841.4mA   -554.7mA
3.86V     -885.5mA   -943.8mA   -742.2mA
5V        -3.006A    -2.53A     -3.767A
[Ramp]
| variable   typ   min   max
dV/dt_r   0.415/0.367n   0.284/0.399n   0.689/0.327n
dV/dt_f   0.460/0.355n   0.303/0.392n   0.677/0.336n
R_load = 50.000
[Rising Waveform]
R_fixture= 50.000
V_fixture= 0.0
V_fixture_min= 0.0
V_fixture_max= 0.0
|time   V(typ)   V(min)   V(max)
0s        9.102nV    62.88nV    33.47nV
596ps     46.79uV    -289.4nV   -13.8mV
766ps     287.1uV    -289.4nV   576.9mV
964ps     -11.14mV   24.31uV    892.4mV
1.072ns   9.243mV    228.8uV    968.7mV
1.396ns   490.1mV    -1.443mV   1.079V
1.842ns   634.2mV    82.19mV    1.127V
2.311ns   670.7mV    394.9mV    1.142V
3.238ns   688mV      462.1mV    1.148V
20ns      691.3mV    473.6mV    1.149V
[Rising Waveform]
R_fixture= 50.000
V_fixture= 2.500
V_fixture_min= 2.380
V_fixture_max= 2.630
|time   V(typ)   V(min)   V(max)
0s        1.731V     1.874V     1.497V
528ps     1.731V     1.874V     1.503V
712ps     1.732V     1.874V     2.319V
894ps     1.729V     1.874V     2.536V
1.168ns   2.293V     1.875V     2.592V
1.319ns   2.414V     1.871V     2.604V
1.476ns   2.451V     1.885V     2.611V
1.883ns   2.481V     2.282V     2.621V
2.38ns    2.492V     2.362V     2.624V
20ns      2.497V     2.379V     2.625V
[Falling Waveform]
R_fixture= 50.000
V_fixture= 2.500
V_fixture_min= 2.380
V_fixture_max= 2.630
|time   V(typ)   V(min)   V(max)
0s        2.497V     2.379V     2.625V
612ps     2.497V     2.379V     2.645V
749ps     2.496V     2.379V     2.151V
823ps     2.497V     2.379V     1.964V
1.091ns   2.518V     2.379V     1.677V
1.403ns   1.981V     2.379V     1.572V
1.82ns    1.802V     2.402V     1.522V
2.372ns   1.752V     1.98V      1.503V
3.02ns    1.737V     1.897V     1.499V
20ns      1.731V     1.874V     1.497V
[Falling Waveform]
R_fixture= 50.000
V_fixture= 0.0
V_fixture_min= 0.0
V_fixture_max= 0.0
|time   V(typ)   V(min)   V(max)
0s        691.3mV    473.6mV    1.149V
568ps     691.3mV    473.6mV    1.136V
700ps     691.2mV    473.7mV    446.5mV
789ps     690.8mV    473.7mV    194.3mV
1.018ns   666.3mV    473.6mV    47.67mV
1.345ns   91.97mV    473.3mV    13.68mV
1.722ns   18.08mV    454mV      3.839mV
2.165ns   5.447mV    61.93mV    979.5uV
2.774ns   1.285mV    8.172mV    234.6uV
20ns      3.151nV    -64.04nV   -165.7nV
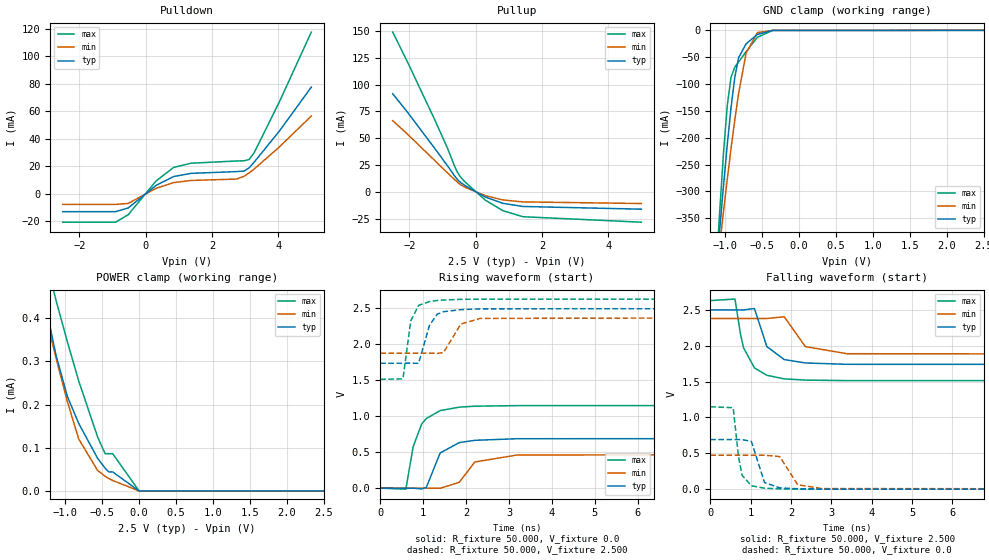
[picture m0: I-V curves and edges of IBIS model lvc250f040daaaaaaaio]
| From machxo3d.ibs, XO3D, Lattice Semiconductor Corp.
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|   Model lvc250f040daaaaaaaio
[Model] lvc250f040daaaaaaaio
Model_type I/O
Polarity   Non-Inverting
Enable   Active-Low
Vinl =  0.700V
Vinh =  1.700V
Vmeas =  1.250V
Cref =  0.0F
Rref =  1.000M
Vref =  0.0V
C_comp   4.200pF   3.800pF   7.500pF
[Temperature Range]   25.000   0.105k   -40.000
[Voltage Range]   2.500V   2.380V   2.630V
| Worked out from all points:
|   slope of the pulldown table from 0 to 0.375 V, typ, clamps not added: 54.4 ohm
|   slope of the pullup table from 0 to 0.375 V, typ, clamps not added: 65.1 ohm
|   GND clamp passes 1 mA (typ) near -0.43 V on its own axis
|   POWER clamp passes 1 mA (typ) near -1.90 V on its own axis
|   rising waveform, R_fixture 50.000, V_fixture 0.0: 20-80 % time 364ps typ, 401ps min, 327ps max; typ from 0 V to 0.691 V
|   rising waveform, R_fixture 50.000, V_fixture 2.500: 20-80 % time 227ps typ, 315ps min, 154ps max; typ from 1.74 V to 2.5 V
|   falling waveform, R_fixture 50.000, V_fixture 2.500: 20-80 % time 362ps typ, 397ps min, 338ps max; typ from 2.5 V to 1.74 V
|   falling waveform, R_fixture 50.000, V_fixture 0.0: 20-80 % time 205ps typ, 286ps min, 145ps max; typ from 0.691 V to 0 V
[Pulldown]
|Voltage   I(typ)   I(min)   I(max)
-2.5V     -13.08mA   -7.815mA   -20.75mA
-904mV    -13.08mA   -7.815mA   -20.75mA
-524mV    -10.41mA   -7.109mA   -15.34mA
312mV     5.902mA    3.803mA    9.102mA
844mV     12.43mA    8.006mA    19.04mA
1.376V    14.74mA    9.586mA    22.12mA
2.744V    16.02mA    10.57mA    23.73mA
2.972V    16.42mA    12.64mA    23.88mA
3.124V    18.76mA    15.12mA    24.81mA
3.276V    22.89mA    17.87mA    29.77mA
4.036V    45.45mA    33.93mA    66.69mA
5V        77.39mA    56.41mA    117.4mA
[Pullup]
|Voltage   I(typ)   I(min)   I(max)
-2.5V     91.47mA    66.45mA    148.9mA
-2.068V   74.85mA    54.31mA    122mA
-1.232V   40.67mA    29.31mA    67.26mA
-852mV    24.62mA    17.98mA    41.17mA
-624mV    14.67mA    11.34mA    23.35mA
-548mV    11.68mA    9.226mA    18.47mA
-472mV    9.383mA    7.274mA    14.7mA
-320mV    5.997mA    4.418mA    9.439mA
288mV     -4.573mA   -3.272mA   -7.415mA
820mV     -10.47mA   -7.36mA    -17.31mA
1.428V    -13.44mA   -9.183mA   -22.98mA
5V        -15.96mA   -10.7mA    -28.07mA
[GND_clamp]
|Voltage   I(typ)   I(min)   I(max)
-2.5V     -2.99A     -2.35A     -4.091A
-1.123V   -455.1mA   -463.2mA   -453.7mA
-1.072V   -370.5mA   -399.5mA   -336.3mA
-1.021V   -289.2mA   -337.4mA   -228.6mA
-970mV    -212.6mA   -277.4mA   -140mA
-919mV    -143.6mA   -220.1mA   -87.4mA
-868mV    -87.39mA   -166.5mA   -68.45mA
-817mV    -50.94mA   -117.8mA   -59.13mA
-715mV    -24.99mA   -42.37mA   -39.7mA
-562mV    -7.608mA   -4.125mA   -12.95mA
-358mV    -194.9uA   -98.36uA   -303.6uA
2.5V      13.17nA    0A         -19.29uA
[POWER_clamp]
|Voltage   I(typ)   I(min)   I(max)
-2.5V     1.538mA    1.365mA    2.125mA
-1.325V   482.6uA    450.2uA    591.5uA
-1.274V   438.4uA    413.8uA    546.6uA
-1.121V   313.5uA    307.1uA    441uA
-968mV    218.6uA    206.5uA    345.2uA
-815mV    156.3uA    120.3uA    254.8uA
-560mV    75.6uA     47.55uA    125.2uA
-458mV    52.75uA    33.88uA    86.35uA
-407mV    44.01uA    28.68uA    86.35uA
-356mV    44.01uA    24.21uA    86.35uA
1mV       0A         0A         141nA
2.5V      0A         0A         0A
[Ramp]
| variable   typ   min   max
dV/dt_r   0.415/0.367n   0.284/0.400n   0.689/0.327n
dV/dt_f   0.457/0.355n   0.302/0.393n   0.670/0.336n
R_load = 50.000
[Rising Waveform]
R_fixture= 50.000
V_fixture= 0.0
V_fixture_min= 0.0
V_fixture_max= 0.0
|time   V(typ)   V(min)   V(max)
0s        9.102nV    62.88nV    33.47nV
596ps     26.05uV    3.623uV    -13.81mV
766ps     322.9uV    3.623uV    576.9mV
964ps     -11.15mV   27.88uV    892.4mV
1.072ns   9.24mV     239uV      968.7mV
1.396ns   490.1mV    -1.477mV   1.079V
1.842ns   634.2mV    82.19mV    1.127V
2.203ns   665.7mV    364.5mV    1.14V
3.186ns   687.6mV    461.1mV    1.148V
20ns      691.3mV    473.6mV    1.149V
[Rising Waveform]
R_fixture= 50.000
V_fixture= 2.500
V_fixture_min= 2.380
V_fixture_max= 2.630
|time   V(typ)   V(min)   V(max)
0s        1.738V     1.877V     1.514V
528ps     1.738V     1.877V     1.52V
711ps     1.739V     1.877V     2.328V
893ps     1.736V     1.877V     2.542V
1.146ns   2.264V     1.878V     2.595V
1.325ns   2.419V     1.874V     2.61V
1.472ns   2.454V     1.886V     2.617V
1.878ns   2.483V     2.282V     2.626V
2.328ns   2.494V     2.361V     2.629V
20ns      2.5V       2.38V      2.63V
[Falling Waveform]
R_fixture= 50.000
V_fixture= 2.500
V_fixture_min= 2.380
V_fixture_max= 2.630
|time   V(typ)   V(min)   V(max)
0s        2.5V       2.38V      2.63V
612ps     2.5V       2.38V      2.651V
749ps     2.499V     2.38V      2.161V
825ps     2.5V       2.38V      1.971V
1.094ns   2.519V     2.38V      1.691V
1.402ns   1.988V     2.38V      1.588V
1.832ns   1.807V     2.404V     1.538V
2.356ns   1.76V      1.988V     1.521V
3.388ns   1.741V     1.889V     1.514V
20ns      1.738V     1.877V     1.514V
[Falling Waveform]
R_fixture= 50.000
V_fixture= 0.0
V_fixture_min= 0.0
V_fixture_max= 0.0
|time   V(typ)   V(min)   V(max)
0s        691.3mV    473.6mV    1.149V
568ps     691.3mV    473.5mV    1.136V
700ps     691.2mV    473.5mV    446.5mV
789ps     690.8mV    473.7mV    194.2mV
1.018ns   666.3mV    473.7mV    47.45mV
1.345ns   92mV       473.3mV    13.62mV
1.722ns   18.12mV    454mV      3.769mV
2.165ns   5.451mV    61.95mV    939.8uV
2.77ns    1.329mV    8.238mV    216.4uV
20ns      1.918nV    -61.27nV   -105.9nV
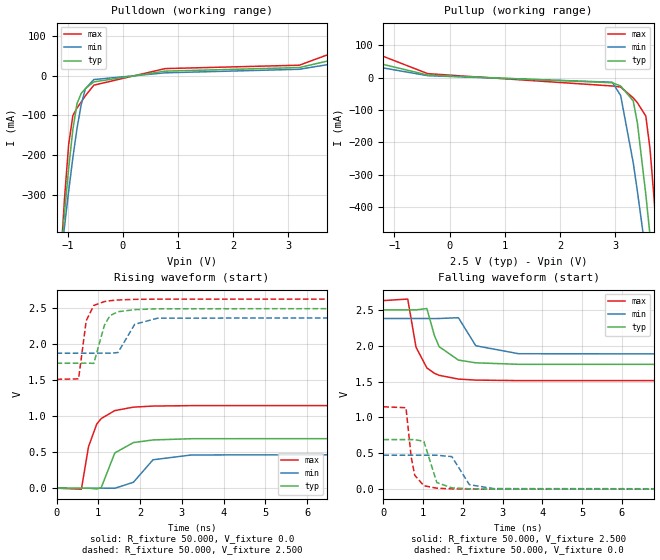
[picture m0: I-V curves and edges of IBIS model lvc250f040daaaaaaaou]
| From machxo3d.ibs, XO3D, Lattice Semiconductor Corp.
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|   Model lvc250f040daaaaaaaou
[Model] lvc250f040daaaaaaaou
Model_type Output
Polarity   Non-Inverting
Enable   Active-High
Vmeas =  1.250V
Cref =  0.0F
Rref =  1.000M
Vref =  0.0V
C_comp   4.200pF   3.800pF   7.500pF
[Temperature Range]   25.000   0.105k   -40.000
[Voltage Range]   2.500V   2.380V   2.630V
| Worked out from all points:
|   slope of the pulldown table from 0 to 0.375 V, typ, clamps not added: 53.8 ohm
|   slope of the pullup table from 0 to 0.375 V, typ, clamps not added: 64.7 ohm
|   rising waveform, R_fixture 50.000, V_fixture 0.0: 20-80 % time 364ps typ, 400ps min, 327ps max; typ from 0 V to 0.691 V
|   rising waveform, R_fixture 50.000, V_fixture 2.500: 20-80 % time 227ps typ, 314ps min, 154ps max; typ from 1.74 V to 2.5 V
|   falling waveform, R_fixture 50.000, V_fixture 2.500: 20-80 % time 360ps typ, 385ps min, 337ps max; typ from 2.5 V to 1.74 V
|   falling waveform, R_fixture 50.000, V_fixture 0.0: 20-80 % time 205ps typ, 286ps min, 145ps max; typ from 0.691 V to 0 V
[Pulldown]
|Voltage   I(typ)   I(min)   I(max)
-2.5V     -2.991A    -2.35A     -4.091A
-1.132V   -472.7mA   -475.7mA   -480.1mA
-1.056V   -348.1mA   -381.3mA   -311.4mA
-980mV    -233.1mA   -290.9mA   -172.7mA
-904mV    -135.4mA   -206.7mA   -100.3mA
-828mV    -69.74mA   -132.1mA   -81mA
-752mV    -44.09mA   -71.81mA   -65.96mA
-676mV    -32.1mA    -32.24mA   -50.01mA
-524mV    -15.15mA   -9.318mA   -23.48mA
768mV     11.87mA    7.615mA    18.3mA
3.2V      20.89mA    16.59mA    26.85mA
5V        78.92mA    57.89mA    119.3mA
[Pullup]
|Voltage   I(typ)   I(min)   I(max)
-2.5V     93.01mA    67.81mA    151mA
-396mV    7.635mA    5.714mA    11.96mA
2.948V    -16.04mA   -14.52mA   -26.02mA
3.1V      -26mA      -55.22mA   -29.32mA
3.328V    -71.93mA   -262.4mA   -62.65mA
3.404V    -140.6mA   -351.2mA   -77.71mA
3.556V    -359.8mA   -541mA     -118.7mA
3.632V    -485.6mA   -639.6mA   -219.2mA
3.708V    -616.1mA   -739.9mA   -376.5mA
3.784V    -749.8mA   -841.4mA   -554.7mA
3.86V     -885.5mA   -943.8mA   -742.2mA
5V        -3.006A    -2.53A     -3.767A
[Ramp]
| variable   typ   min   max
dV/dt_r   0.415/0.367n   0.284/0.399n   0.689/0.327n
dV/dt_f   0.457/0.355n   0.302/0.393n   0.670/0.336n
R_load = 50.000
[Rising Waveform]
R_fixture= 50.000
V_fixture= 0.0
V_fixture_min= 0.0
V_fixture_max= 0.0
|time   V(typ)   V(min)   V(max)
0s        9.102nV    62.88nV    33.47nV
596ps     46.79uV    -320.3nV   -13.8mV
766ps     287.1uV    -320.3nV   576.9mV
964ps     -11.14mV   24.3uV     892.4mV
1.072ns   9.243mV    228.8uV    968.7mV
1.396ns   490.1mV    -1.443mV   1.079V
1.842ns   634.2mV    82.19mV    1.127V
2.311ns   670.7mV    394.9mV    1.142V
3.238ns   688mV      462.1mV    1.148V
20ns      691.3mV    473.6mV    1.149V
[Rising Waveform]
R_fixture= 50.000
V_fixture= 2.500
V_fixture_min= 2.380
V_fixture_max= 2.630
|time   V(typ)   V(min)   V(max)
0s        1.738V     1.877V     1.514V
528ps     1.738V     1.877V     1.52V
711ps     1.739V     1.877V     2.328V
893ps     1.736V     1.877V     2.542V
1.146ns   2.264V     1.878V     2.595V
1.276ns   2.397V     1.877V     2.607V
1.472ns   2.454V     1.886V     2.617V
1.873ns   2.483V     2.279V     2.626V
2.419ns   2.495V     2.364V     2.629V
20ns      2.5V       2.38V      2.63V
[Falling Waveform]
R_fixture= 50.000
V_fixture= 2.500
V_fixture_min= 2.380
V_fixture_max= 2.630
|time   V(typ)   V(min)   V(max)
0s        2.5V       2.38V      2.63V
612ps     2.5V       2.38V      2.651V
821ps     2.5V       2.38V      1.979V
1.094ns   2.519V     2.38V      1.691V
1.283ns   2.143V     2.379V     1.616V
1.403ns   1.987V     2.38V      1.588V
1.888ns   1.8V       2.391V     1.535V
2.325ns   1.762V     2V         1.521V
3.402ns   1.741V     1.889V     1.514V
20ns      1.738V     1.877V     1.514V
[Falling Waveform]
R_fixture= 50.000
V_fixture= 0.0
V_fixture_min= 0.0
V_fixture_max= 0.0
|time   V(typ)   V(min)   V(max)
0s        691.3mV    473.6mV    1.149V
568ps     691.3mV    473.6mV    1.136V
700ps     691.2mV    473.7mV    446.5mV
789ps     690.8mV    473.7mV    194.3mV
1.018ns   666.3mV    473.6mV    47.67mV
1.345ns   91.97mV    473.3mV    13.68mV
1.722ns   18.08mV    454mV      3.839mV
2.165ns   5.447mV    61.93mV    979.5uV
2.774ns   1.285mV    8.172mV    234.6uV
20ns      3.191nV    -64.04nV   -165.7nV
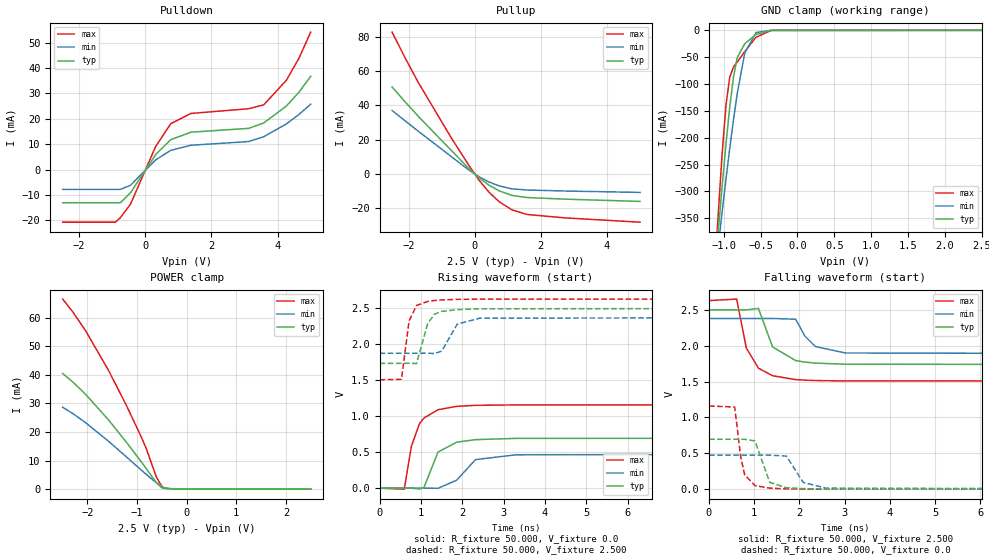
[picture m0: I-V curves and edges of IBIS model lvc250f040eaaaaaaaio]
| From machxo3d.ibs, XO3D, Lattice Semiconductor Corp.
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|   Model lvc250f040eaaaaaaaio
[Model] lvc250f040eaaaaaaaio
Model_type I/O
Polarity   Non-Inverting
Enable   Active-Low
Vinl =  0.700V
Vinh =  1.700V
Vmeas =  1.250V
Cref =  0.0F
Rref =  1.000M
Vref =  0.0V
C_comp   4.200pF   3.800pF   7.500pF
[Temperature Range]   25.000   0.105k   -40.000
[Voltage Range]   2.500V   2.380V   2.630V
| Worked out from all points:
|   slope of the pulldown table from 0 to 0.375 V, typ, clamps not added: 54.4 ohm
|   slope of the pullup table from 0 to 0.375 V, typ, clamps not added: 65.1 ohm
|   GND clamp passes 1 mA (typ) near -0.43 V on its own axis
|   POWER clamp passes 1 mA (typ) near -0.54 V on its own axis
|   rising waveform, R_fixture 50.000, V_fixture 0.0: 20-80 % time 365ps typ, 400ps min, 329ps max; typ from 0 V to 0.696 V
|   rising waveform, R_fixture 50.000, V_fixture 2.500: 20-80 % time 226ps typ, 315ps min, 154ps max; typ from 1.74 V to 2.5 V
|   falling waveform, R_fixture 50.000, V_fixture 2.500: 20-80 % time 361ps typ, 399ps min, 339ps max; typ from 2.5 V to 1.74 V
|   falling waveform, R_fixture 50.000, V_fixture 0.0: 20-80 % time 205ps typ, 285ps min, 147ps max; typ from 0.696 V to 0 V
[Pulldown]
|Voltage   I(typ)   I(min)   I(max)
-2.5V     -13.08mA   -7.815mA   -20.75mA
-904mV    -13.08mA   -7.815mA   -20.75mA
-752mV    -13.08mA   -7.815mA   -18.92mA
-448mV    -9.14mA    -6.165mA   -13.6mA
312mV     5.902mA    3.803mA    9.102mA
768mV     11.78mA    7.58mA     18.08mA
1.376V    14.74mA    9.586mA    22.12mA
3.124V    16.24mA    11.04mA    23.98mA
3.58V     18.37mA    12.97mA    25.51mA
4.264V    25.05mA    17.98mA    35.2mA
4.644V    30.48mA    21.72mA    43.85mA
5V        36.76mA    25.77mA    54.2mA
[Pullup]
|Voltage   I(typ)   I(min)   I(max)
-2.5V     50.81mA    37.11mA    82.8mA
-2.068V   41.35mA    30.49mA    66.4mA
-1.688V   33.31mA    24.71mA    52.81mA
-700mV    13.64mA    10.08mA    20.84mA
-168mV    3.057mA    2.23mA     4.86mA
136mV     -2.284mA   -1.64mA    -3.687mA
440mV     -6.588mA   -4.693mA   -10.74mA
744mV     -9.822mA   -6.926mA   -16.19mA
1.124V    -12.43mA   -8.62mA    -20.86mA
1.58V     -13.68mA   -9.308mA   -23.56mA
2.72V     -14.62mA   -9.887mA   -25.54mA
5V        -15.96mA   -10.7mA    -28.07mA
[GND_clamp]
|Voltage   I(typ)   I(min)   I(max)
-2.5V     -2.99A     -2.35A     -4.091A
-1.123V   -455.1mA   -463.2mA   -453.6mA
-1.072V   -370.5mA   -399.5mA   -336.3mA
-1.021V   -289.1mA   -337.4mA   -228.5mA
-970mV    -212.6mA   -277.3mA   -139.9mA
-919mV    -143.6mA   -220.1mA   -87.34mA
-868mV    -87.35mA   -166.5mA   -68.39mA
-817mV    -50.9mA    -117.8mA   -59.07mA
-715mV    -24.94mA   -42.34mA   -39.63mA
-562mV    -7.547mA   -4.077mA   -12.85mA
-358mV    -114uA     -53.77uA   -172.8uA
2.5V      0A         0A         0A
[POWER_clamp]
|Voltage   I(typ)   I(min)   I(max)
-2.5V     40.49mA    28.66mA    66.53mA
-2.294V   37.48mA    26.44mA    61.99mA
-2.039V   33.22mA    23.28mA    55.47mA
-1.58V    24.32mA    16.83mA    41.7mA
-1.223V   16.6mA     11.41mA    29.58mA
-917mV    9.616mA    6.712mA    18.32mA
-815mV    7.205mA    5.171mA    14.19mA
-611mV    2.275mA    2.213mA    4.254mA
-509mV    589.4uA    929.1uA    1.152mA
-458mV    232.9uA    445.2uA    427.7uA
-254mV    3.785uA    4.472uA    4.114uA
2.5V      0A         0A         3.667nA
[Ramp]
| variable   typ   min   max
dV/dt_r   0.417/0.370n   0.285/0.401n   0.695/0.328n
dV/dt_f   0.459/0.355n   0.303/0.392n   0.673/0.337n
R_load = 50.000
[Rising Waveform]
R_fixture= 50.000
V_fixture= 0.0
V_fixture_min= 0.0
V_fixture_max= 0.0
|time   V(typ)   V(min)   V(max)
0s        9.431nV    63.61nV    34.88nV
596ps     26.19uV    3.712uV    -13.84mV
767ps     327.1uV    3.712uV    581mV
963ps     -11.16mV   27.93uV    897.3mV
1.072ns   9.193mV    239.3uV    975.4mV
1.411ns   501.9mV    -2.007mV   1.091V
1.863ns   639.7mV    111mV      1.138V
2.318ns   674.9mV    397.1mV    1.152V
3.299ns   692.7mV    464.6mV    1.158V
20ns      695.7mV    475.1mV    1.159V
[Rising Waveform]
R_fixture= 50.000
V_fixture= 2.500
V_fixture_min= 2.380
V_fixture_max= 2.630
|time   V(typ)   V(min)   V(max)
0s        1.736V     1.876V     1.508V
528ps     1.736V     1.876V     1.514V
712ps     1.737V     1.876V     2.327V
892ps     1.733V     1.876V     2.541V
1.163ns   2.29V      1.877V     2.597V
1.329ns   2.421V     1.872V     2.61V
1.5ns     2.458V     1.905V     2.618V
1.878ns   2.483V     2.282V     2.626V
2.42ns    2.495V     2.364V     2.629V
20ns      2.5V       2.38V      2.63V
[Falling Waveform]
R_fixture= 50.000
V_fixture= 2.500
V_fixture_min= 2.380
V_fixture_max= 2.630
|time   V(typ)   V(min)   V(max)
0s        2.5V       2.38V      2.63V
612ps     2.5V       2.38V      2.651V
825ps     2.5V       2.38V      1.969V
1.093ns   2.52V      2.38V      1.687V
1.406ns   1.983V     2.38V      1.582V
1.916ns   1.793V     2.37V      1.528V
2.121ns   1.772V     2.134V     1.52V
2.352ns   1.758V     1.989V     1.515V
3.016ns   1.742V     1.899V     1.509V
20ns      1.736V     1.876V     1.508V
[Falling Waveform]
R_fixture= 50.000
V_fixture= 0.0
V_fixture_min= 0.0
V_fixture_max= 0.0
|time   V(typ)   V(min)   V(max)
0s        695.7mV    475.1mV    1.159V
568ps     695.7mV    475mV      1.146V
701ps     695.6mV    475.2mV    450.3mV
789ps     695.2mV    475.2mV    200.1mV
1.016ns   672.8mV    475.2mV    50mV
1.343ns   95.11mV    474.7mV    14.22mV
1.712ns   19.4mV     461.3mV    4.057mV
2.082ns   7.345mV    94.65mV    1.317mV
2.592ns   1.991mV    13.06mV    282.7uV
20ns      -248nV     114.1nV    -303.2nV
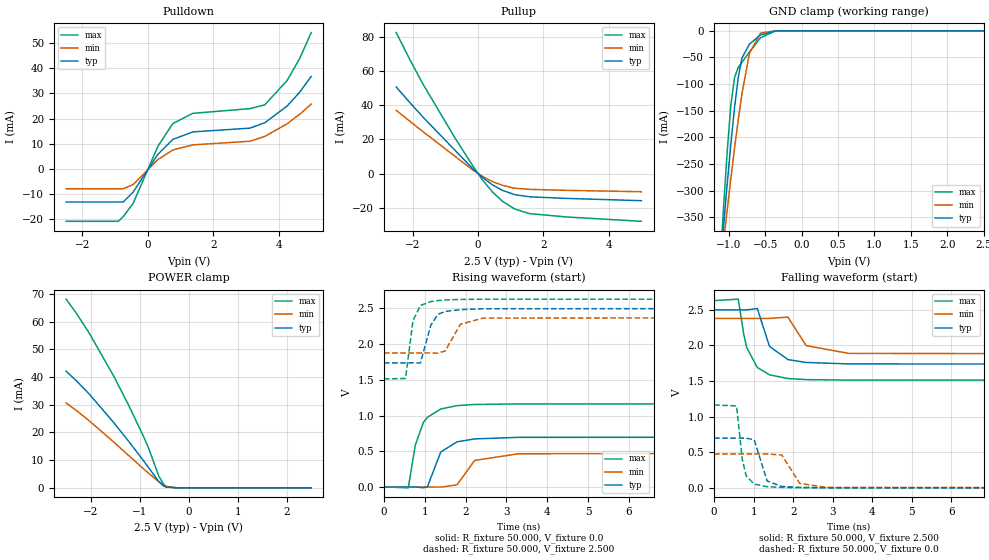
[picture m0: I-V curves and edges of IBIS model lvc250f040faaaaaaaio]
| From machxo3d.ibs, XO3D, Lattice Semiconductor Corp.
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|   Model lvc250f040faaaaaaaio
[Model] lvc250f040faaaaaaaio
Model_type I/O
Polarity   Non-Inverting
Enable   Active-Low
Vinl =  0.700V
Vinh =  1.700V
Vmeas =  1.250V
Cref =  0.0F
Rref =  1.000M
Vref =  0.0V
C_comp   4.200pF   3.800pF   7.500pF
[Temperature Range]   25.000   0.105k   -40.000
[Voltage Range]   2.500V   2.380V   2.630V
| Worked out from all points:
|   slope of the pulldown table from 0 to 0.375 V, typ, clamps not added: 54.4 ohm
|   slope of the pullup table from 0 to 0.375 V, typ, clamps not added: 65.1 ohm
|   GND clamp passes 1 mA (typ) near -0.43 V on its own axis
|   POWER clamp passes 1 mA (typ) near -0.54 V on its own axis
|   rising waveform, R_fixture 50.000, V_fixture 0.0: 20-80 % time 369ps typ, 403ps min, 328ps max; typ from 0.002 V to 0.7 V
|   rising waveform, R_fixture 50.000, V_fixture 2.500: 20-80 % time 227ps typ, 314ps min, 154ps max; typ from 1.74 V to 2.5 V
|   falling waveform, R_fixture 50.000, V_fixture 2.500: 20-80 % time 361ps typ, 384ps min, 338ps max; typ from 2.5 V to 1.74 V
|   falling waveform, R_fixture 50.000, V_fixture 0.0: 20-80 % time 205ps typ, 288ps min, 148ps max; typ from 0.7 V to 0.002 V
[Pulldown]
|Voltage   I(typ)   I(min)   I(max)
-2.5V     -13.08mA   -7.815mA   -20.75mA
-904mV    -13.08mA   -7.815mA   -20.75mA
-752mV    -13.08mA   -7.815mA   -18.92mA
-448mV    -9.14mA    -6.165mA   -13.6mA
312mV     5.902mA    3.803mA    9.102mA
768mV     11.78mA    7.58mA     18.08mA
1.376V    14.74mA    9.586mA    22.12mA
3.124V    16.24mA    11.04mA    23.98mA
3.58V     18.37mA    12.97mA    25.51mA
4.264V    25.04mA    17.98mA    35.2mA
4.644V    30.48mA    21.72mA    43.84mA
5V        36.75mA    25.77mA    54.19mA
[Pullup]
|Voltage   I(typ)   I(min)   I(max)
-2.5V     50.84mA    37.13mA    82.83mA
-2.068V   41.36mA    30.5mA     66.4mA
-1.688V   33.32mA    24.71mA    52.81mA
-700mV    13.64mA    10.08mA    20.84mA
-168mV    3.057mA    2.23mA     4.86mA
136mV     -2.284mA   -1.64mA    -3.687mA
440mV     -6.588mA   -4.693mA   -10.74mA
744mV     -9.822mA   -6.926mA   -16.19mA
1.124V    -12.43mA   -8.62mA    -20.86mA
1.58V     -13.68mA   -9.308mA   -23.56mA
2.72V     -14.62mA   -9.887mA   -25.54mA
5V        -15.96mA   -10.7mA    -28.07mA
[GND_clamp]
|Voltage   I(typ)   I(min)   I(max)
-2.5V     -2.99A     -2.35A     -4.091A
-1.123V   -455.1mA   -463.2mA   -453.7mA
-1.072V   -370.5mA   -399.5mA   -336.3mA
-1.021V   -289.2mA   -337.4mA   -228.6mA
-970mV    -212.6mA   -277.4mA   -140mA
-919mV    -143.6mA   -220.1mA   -87.39mA
-868mV    -87.38mA   -166.5mA   -68.44mA
-817mV    -50.93mA   -117.8mA   -59.12mA
-715mV    -24.98mA   -42.36mA   -39.69mA
-562mV    -7.596mA   -4.111mA   -12.93mA
-358mV    -193.4uA   -101.2uA   -309.3uA
2.5V      13.17nA    0A         -19.29uA
[POWER_clamp]
|Voltage   I(typ)   I(min)   I(max)
-2.5V     42.14mA    30.66mA    68.15mA
-2.294V   38.75mA    27.99mA    63.15mA
-2.039V   34.09mA    24.4mA     56.2mA
-1.529V   23.59mA    16.56mA    40.38mA
-1.223V   16.79mA    11.66mA    29.8mA
-917mV    9.72mA     6.817mA    18.42mA
-815mV    7.285mA    5.246mA    14.27mA
-611mV    2.32mA     2.253mA    4.314mA
-509mV    627.1uA    959.6uA    1.202mA
-458mV    269.3uA    472.4uA    476.3uA
-254mV    28.45uA    20.72uA    43.74uA
2.5V      0A         0A         0A
[Ramp]
| variable   typ   min   max
dV/dt_r   0.419/0.369n   0.286/0.401n   0.697/0.327n
dV/dt_f   0.457/0.355n   0.302/0.393n   0.670/0.336n
R_load = 50.000
[Rising Waveform]
R_fixture= 50.000
V_fixture= 0.0
V_fixture_min= 0.0
V_fixture_max= 0.0
|time   V(typ)   V(min)   V(max)
0s        2.016mV    1.415mV    2.955mV
596ps     2.067mV    1.417mV    -10.34mV
767ps     2.318mV    1.417mV    586.8mV
965ps     -9.194mV   1.441mV    905.5mV
1.064ns   4.222mV    1.644mV    976.9mV
1.39ns    490.9mV    -6.982uV   1.093V
1.789ns   633.8mV    31.71mV    1.14V
2.221ns   674.4mV    373.5mV    1.156V
3.301ns   696.6mV    467mV      1.164V
20ns      699.6mV    477.4mV    1.165V
[Rising Waveform]
R_fixture= 50.000
V_fixture= 2.500
V_fixture_min= 2.380
V_fixture_max= 2.630
|time   V(typ)   V(min)   V(max)
0s        1.738V     1.877V     1.514V
528ps     1.738V     1.877V     1.52V
711ps     1.739V     1.877V     2.328V
893ps     1.736V     1.877V     2.542V
1.146ns   2.264V     1.878V     2.595V
1.325ns   2.419V     1.874V     2.61V
1.498ns   2.458V     1.905V     2.618V
1.873ns   2.483V     2.279V     2.626V
2.421ns   2.495V     2.364V     2.629V
20ns      2.5V       2.38V      2.63V
[Falling Waveform]
R_fixture= 50.000
V_fixture= 2.500
V_fixture_min= 2.380
V_fixture_max= 2.630
|time   V(typ)   V(min)   V(max)
0s        2.5V       2.38V      2.63V
612ps     2.5V       2.38V      2.651V
749ps     2.499V     2.38V      2.161V
825ps     2.5V       2.38V      1.971V
1.094ns   2.519V     2.38V      1.691V
1.403ns   1.987V     2.38V      1.588V
1.868ns   1.802V     2.399V     1.536V
2.33ns    1.762V     1.998V     1.521V
3.411ns   1.741V     1.889V     1.514V
20ns      1.738V     1.877V     1.514V
[Falling Waveform]
R_fixture= 50.000
V_fixture= 0.0
V_fixture_min= 0.0
V_fixture_max= 0.0
|time   V(typ)   V(min)   V(max)
0s        699.6mV    477.4mV    1.165V
568ps     699.6mV    477.3mV    1.152V
714ps     699.4mV    477.5mV    400.8mV
812ps     699.3mV    477.5mV    170.8mV
1.016ns   676.8mV    477.5mV    53.32mV
1.341ns   98.78mV    477mV      17.37mV
1.713ns   21.21mV    463.1mV    7.132mV
2.167ns   7.611mV    63.7mV     4.1mV
2.836ns   3.179mV    8.651mV    3.145mV
20ns      2.016mV    1.415mV    2.955mV
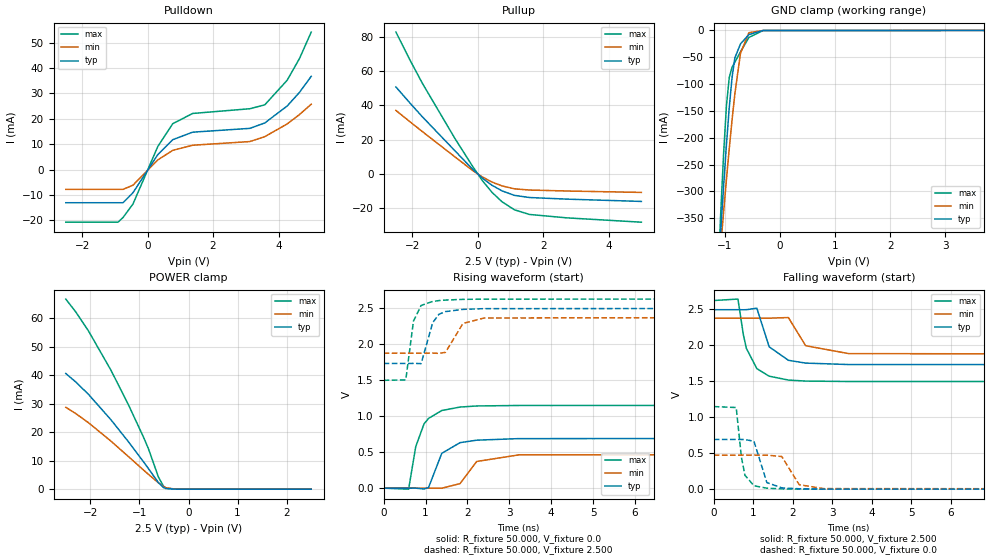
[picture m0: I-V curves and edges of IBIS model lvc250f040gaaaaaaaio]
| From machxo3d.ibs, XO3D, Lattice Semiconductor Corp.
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|   Model lvc250f040gaaaaaaaio
[Model] lvc250f040gaaaaaaaio
Model_type I/O
Polarity   Non-Inverting
Enable   Active-Low
Vinl =  0.700V
Vinh =  1.700V
Vmeas =  1.250V
Cref =  0.0F
Rref =  1.000M
Vref =  0.0V
C_comp   4.200pF   3.800pF   7.500pF
[Temperature Range]   25.000   0.105k   -40.000
[Voltage Range]   2.500V   2.380V   2.630V
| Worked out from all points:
|   slope of the pulldown table from 0 to 0.375 V, typ, clamps not added: 54.4 ohm
|   slope of the pullup table from 0 to 0.375 V, typ, clamps not added: 65.1 ohm
|   GND clamp passes 1 mA (typ) near -0.43 V on its own axis
|   POWER clamp passes 1 mA (typ) near -0.54 V on its own axis
|   rising waveform, R_fixture 50.000, V_fixture 0.0: 20-80 % time 363ps typ, 399ps min, 327ps max; typ from 0 V to 0.691 V
|   rising waveform, R_fixture 50.000, V_fixture 2.500: 20-80 % time 227ps typ, 317ps min, 155ps max; typ from 1.73 V to 2.5 V
|   falling waveform, R_fixture 50.000, V_fixture 2.500: 20-80 % time 358ps typ, 399ps min, 339ps max; typ from 2.5 V to 1.73 V
|   falling waveform, R_fixture 50.000, V_fixture 0.0: 20-80 % time 205ps typ, 286ps min, 145ps max; typ from 0.691 V to 0 V
[Pulldown]
|Voltage   I(typ)   I(min)   I(max)
-2.5V     -13.08mA   -7.815mA   -20.75mA
-904mV    -13.08mA   -7.815mA   -20.75mA
-752mV    -13.08mA   -7.815mA   -18.92mA
-448mV    -9.14mA    -6.165mA   -13.6mA
312mV     5.902mA    3.803mA    9.102mA
768mV     11.78mA    7.58mA     18.08mA
1.376V    14.74mA    9.586mA    22.12mA
3.124V    16.24mA    11.04mA    23.98mA
3.58V     18.37mA    12.97mA    25.51mA
4.264V    25.04mA    17.98mA    35.2mA
4.644V    30.48mA    21.72mA    43.85mA
5V        36.76mA    25.77mA    54.2mA
[Pullup]
|Voltage   I(typ)   I(min)   I(max)
-2.5V     50.81mA    37.11mA    82.81mA
-2.068V   41.35mA    30.49mA    66.4mA
-1.688V   33.32mA    24.71mA    52.81mA
-700mV    13.64mA    10.08mA    20.84mA
-168mV    3.057mA    2.23mA     4.86mA
136mV     -2.284mA   -1.64mA    -3.687mA
440mV     -6.588mA   -4.693mA   -10.74mA
744mV     -9.822mA   -6.926mA   -16.19mA
1.124V    -12.43mA   -8.62mA    -20.86mA
1.58V     -13.68mA   -9.308mA   -23.56mA
2.72V     -14.62mA   -9.887mA   -25.54mA
5V        -15.96mA   -10.7mA    -28.07mA
[GND_clamp]
|Voltage   I(typ)   I(min)   I(max)
-2.5V     -2.99A     -2.35A     -4.091A
-1.123V   -455.1mA   -463.2mA   -453.7mA
-1.072V   -370.5mA   -399.5mA   -336.3mA
-1.021V   -289.2mA   -337.4mA   -228.6mA
-970mV    -212.6mA   -277.4mA   -140mA
-919mV    -143.6mA   -220.1mA   -87.4mA
-868mV    -87.39mA   -166.5mA   -68.45mA
-817mV    -50.94mA   -117.8mA   -59.13mA
-715mV    -24.99mA   -42.37mA   -39.7mA
-562mV    -7.608mA   -4.125mA   -12.95mA
-307mV    -97.66uA   -51.76uA   -173.8uA
5V        114uA      49.35uA    266.8uA
[POWER_clamp]
|Voltage   I(typ)   I(min)   I(max)
-2.5V     40.55mA    28.7mA     66.64mA
-2.294V   37.53mA    26.47mA    62.05mA
-2.039V   33.25mA    23.31mA    55.5mA
-1.58V    24.33mA    16.84mA    41.69mA
-1.223V   16.6mA     11.41mA    29.54mA
-917mV    9.596mA    6.709mA    18.24mA
-815mV    7.18mA     5.166mA    14.11mA
-611mV    2.243mA    2.205mA    4.167mA
-509mV    558uA      921.7uA    1.059mA
-458mV    208uA      438.7uA    350.8uA
-254mV    2.162uA    3.635uA    1.029uA
2.5V      0A         0A         0A
[Ramp]
| variable   typ   min   max
dV/dt_r   0.415/0.367n   0.284/0.400n   0.689/0.327n
dV/dt_f   0.460/0.355n   0.303/0.392n   0.677/0.336n
R_load = 50.000
[Rising Waveform]
R_fixture= 50.000
V_fixture= 0.0
V_fixture_min= 0.0
V_fixture_max= 0.0
|time   V(typ)   V(min)   V(max)
0s        9.102nV    62.88nV    33.47nV
596ps     26.07uV    3.65uV     -13.81mV
766ps     322.9uV    3.65uV     576.9mV
964ps     -11.15mV   27.88uV    892.4mV
1.072ns   9.24mV     239uV      968.7mV
1.387ns   483.5mV    -1.092mV   1.078V
1.824ns   632.1mV    63.33mV    1.126V
2.221ns   666.2mV    370.5mV    1.141V
3.222ns   687.9mV    461.8mV    1.148V
20ns      691.3mV    473.6mV    1.149V
[Rising Waveform]
R_fixture= 50.000
V_fixture= 2.500
V_fixture_min= 2.380
V_fixture_max= 2.630
|time   V(typ)   V(min)   V(max)
0s        1.731V     1.874V     1.497V
528ps     1.731V     1.874V     1.503V
712ps     1.732V     1.874V     2.319V
894ps     1.729V     1.874V     2.536V
1.17ns    2.296V     1.875V     2.592V
1.319ns   2.414V     1.871V     2.604V
1.476ns   2.451V     1.885V     2.611V
1.893ns   2.482V     2.287V     2.621V
2.399ns   2.492V     2.362V     2.624V
20ns      2.497V     2.379V     2.625V
[Falling Waveform]
R_fixture= 50.000
V_fixture= 2.500
V_fixture_min= 2.380
V_fixture_max= 2.630
|time   V(typ)   V(min)   V(max)
0s        2.497V     2.379V     2.625V
612ps     2.497V     2.379V     2.645V
749ps     2.496V     2.379V     2.151V
825ps     2.497V     2.379V     1.96V
1.091ns   2.518V     2.379V     1.677V
1.403ns   1.981V     2.379V     1.572V
1.89ns    1.793V     2.388V     1.518V
2.328ns   1.754V     1.996V     1.504V
3.42ns    1.734V     1.886V     1.498V
20ns      1.731V     1.874V     1.497V
[Falling Waveform]
R_fixture= 50.000
V_fixture= 0.0
V_fixture_min= 0.0
V_fixture_max= 0.0
|time   V(typ)   V(min)   V(max)
0s        691.3mV    473.6mV    1.149V
568ps     691.3mV    473.5mV    1.136V
700ps     691.2mV    473.5mV    446.5mV
789ps     690.8mV    473.7mV    194.2mV
1.018ns   666.3mV    473.7mV    47.45mV
1.345ns   92mV       473.3mV    13.62mV
1.722ns   18.12mV    454.1mV    3.769mV
2.165ns   5.451mV    61.95mV    939.8uV
2.77ns    1.329mV    8.238mV    216.4uV
20ns      1.918nV    -61.27nV   -105.9nV
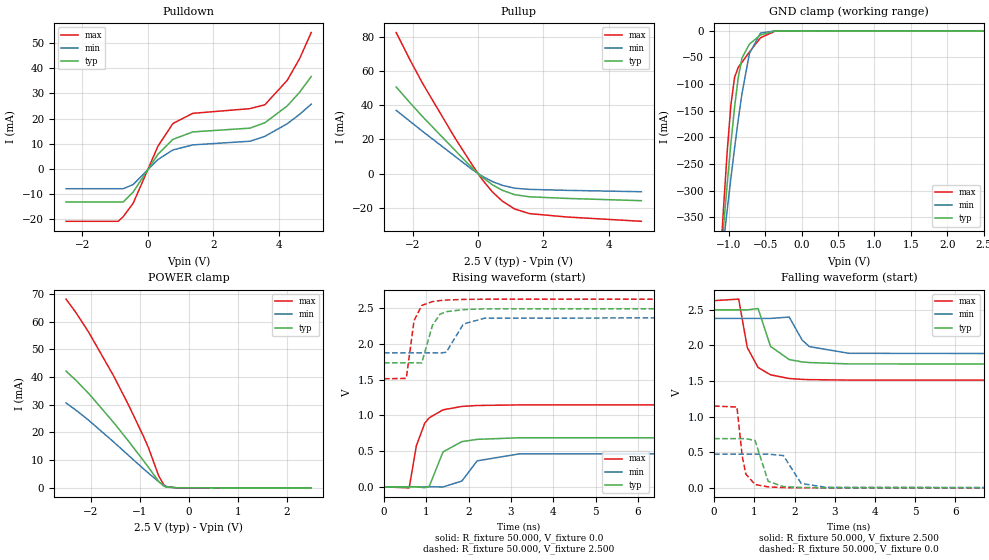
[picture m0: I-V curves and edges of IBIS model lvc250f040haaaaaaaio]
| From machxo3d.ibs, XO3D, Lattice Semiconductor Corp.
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|   Model lvc250f040haaaaaaaio
[Model] lvc250f040haaaaaaaio
Model_type I/O
Polarity   Non-Inverting
Enable   Active-Low
Vinl =  0.700V
Vinh =  1.700V
Vmeas =  1.250V
Cref =  0.0F
Rref =  1.000M
Vref =  0.0V
C_comp   4.200pF   3.800pF   7.500pF
[Temperature Range]   25.000   0.105k   -40.000
[Voltage Range]   2.500V   2.380V   2.630V
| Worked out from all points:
|   slope of the pulldown table from 0 to 0.375 V, typ, clamps not added: 54.4 ohm
|   slope of the pullup table from 0 to 0.375 V, typ, clamps not added: 65.1 ohm
|   GND clamp passes 1 mA (typ) near -0.43 V on its own axis
|   POWER clamp passes 1 mA (typ) near -0.54 V on its own axis
|   rising waveform, R_fixture 50.000, V_fixture 0.0: 20-80 % time 364ps typ, 401ps min, 327ps max; typ from 0 V to 0.691 V
|   rising waveform, R_fixture 50.000, V_fixture 2.500: 20-80 % time 227ps typ, 315ps min, 154ps max; typ from 1.74 V to 2.5 V
|   falling waveform, R_fixture 50.000, V_fixture 2.500: 20-80 % time 361ps typ, 397ps min, 338ps max; typ from 2.5 V to 1.74 V
|   falling waveform, R_fixture 50.000, V_fixture 0.0: 20-80 % time 205ps typ, 286ps min, 145ps max; typ from 0.691 V to 0 V
[Pulldown]
|Voltage   I(typ)   I(min)   I(max)
-2.5V     -13.08mA   -7.815mA   -20.75mA
-904mV    -13.08mA   -7.815mA   -20.75mA
-752mV    -13.08mA   -7.815mA   -18.92mA
-448mV    -9.14mA    -6.165mA   -13.6mA
312mV     5.902mA    3.803mA    9.102mA
768mV     11.78mA    7.58mA     18.08mA
1.376V    14.74mA    9.586mA    22.12mA
3.124V    16.24mA    11.04mA    23.98mA
3.58V     18.37mA    12.97mA    25.51mA
4.264V    25.04mA    17.98mA    35.2mA
4.644V    30.48mA    21.72mA    43.84mA
5V        36.75mA    25.77mA    54.19mA
[Pullup]
|Voltage   I(typ)   I(min)   I(max)
-2.5V     50.84mA    37.13mA    82.83mA
-2.068V   41.36mA    30.5mA     66.4mA
-1.688V   33.32mA    24.71mA    52.81mA
-700mV    13.64mA    10.08mA    20.84mA
-168mV    3.057mA    2.23mA     4.86mA
136mV     -2.284mA   -1.64mA    -3.687mA
440mV     -6.588mA   -4.693mA   -10.74mA
744mV     -9.822mA   -6.926mA   -16.19mA
1.124V    -12.43mA   -8.62mA    -20.86mA
1.58V     -13.68mA   -9.308mA   -23.56mA
2.72V     -14.62mA   -9.887mA   -25.54mA
5V        -15.96mA   -10.7mA    -28.07mA
[GND_clamp]
|Voltage   I(typ)   I(min)   I(max)
-2.5V     -2.99A     -2.35A     -4.091A
-1.123V   -455.1mA   -463.2mA   -453.7mA
-1.072V   -370.5mA   -399.5mA   -336.3mA
-1.021V   -289.2mA   -337.4mA   -228.6mA
-970mV    -212.6mA   -277.4mA   -140mA
-919mV    -143.6mA   -220.1mA   -87.4mA
-868mV    -87.39mA   -166.5mA   -68.45mA
-817mV    -50.94mA   -117.8mA   -59.13mA
-715mV    -24.99mA   -42.37mA   -39.7mA
-562mV    -7.608mA   -4.125mA   -12.95mA
-358mV    -194.9uA   -98.36uA   -303.6uA
2.5V      13.17nA    0A         -19.29uA
[POWER_clamp]
|Voltage   I(typ)   I(min)   I(max)
-2.5V     42.14mA    30.66mA    68.15mA
-2.294V   38.75mA    27.99mA    63.15mA
-2.039V   34.09mA    24.4mA     56.2mA
-1.529V   23.59mA    16.56mA    40.38mA
-1.223V   16.79mA    11.66mA    29.8mA
-917mV    9.72mA     6.817mA    18.42mA
-815mV    7.285mA    5.246mA    14.27mA
-611mV    2.32mA     2.253mA    4.314mA
-509mV    627.1uA    959.6uA    1.202mA
-458mV    269.3uA    472.4uA    476.3uA
-254mV    28.45uA    20.72uA    43.74uA
2.5V      0A         0A         0A
[Ramp]
| variable   typ   min   max
dV/dt_r   0.415/0.367n   0.284/0.400n   0.689/0.327n
dV/dt_f   0.457/0.355n   0.302/0.393n   0.670/0.336n
R_load = 50.000
[Rising Waveform]
R_fixture= 50.000
V_fixture= 0.0
V_fixture_min= 0.0
V_fixture_max= 0.0
|time   V(typ)   V(min)   V(max)
0s        9.102nV    62.88nV    33.47nV
596ps     26.05uV    3.622uV    -13.81mV
766ps     322.9uV    3.622uV    576.9mV
964ps     -11.15mV   27.88uV    892.4mV
1.072ns   9.24mV     239uV      968.7mV
1.396ns   490.1mV    -1.477mV   1.079V
1.842ns   634.2mV    82.19mV    1.127V
2.203ns   665.7mV    364.5mV    1.14V
3.186ns   687.6mV    461.1mV    1.148V
20ns      691.3mV    473.6mV    1.149V
[Rising Waveform]
R_fixture= 50.000
V_fixture= 2.500
V_fixture_min= 2.380
V_fixture_max= 2.630
|time   V(typ)   V(min)   V(max)
0s        1.738V     1.877V     1.514V
528ps     1.738V     1.877V     1.52V
711ps     1.739V     1.877V     2.328V
893ps     1.736V     1.877V     2.542V
1.146ns   2.264V     1.878V     2.595V
1.325ns   2.419V     1.874V     2.61V
1.472ns   2.454V     1.886V     2.617V
1.878ns   2.483V     2.282V     2.626V
2.38ns    2.494V     2.363V     2.629V
20ns      2.5V       2.38V      2.63V
[Falling Waveform]
R_fixture= 50.000
V_fixture= 2.500
V_fixture_min= 2.380
V_fixture_max= 2.630
|time   V(typ)   V(min)   V(max)
0s        2.5V       2.38V      2.63V
612ps     2.5V       2.38V      2.651V
825ps     2.5V       2.38V      1.971V
1.094ns   2.519V     2.38V      1.691V
1.403ns   1.987V     2.38V      1.588V
1.868ns   1.802V     2.399V     1.536V
2.188ns   1.769V     2.077V     1.524V
2.369ns   1.76V      1.984V     1.52V
3.352ns   1.741V     1.89V      1.514V
20ns      1.738V     1.877V     1.514V
[Falling Waveform]
R_fixture= 50.000
V_fixture= 0.0
V_fixture_min= 0.0
V_fixture_max= 0.0
|time   V(typ)   V(min)   V(max)
0s        691.3mV    473.6mV    1.149V
568ps     691.3mV    473.5mV    1.136V
700ps     691.2mV    473.5mV    446.5mV
789ps     690.8mV    473.7mV    194.2mV
1.018ns   666.3mV    473.7mV    47.45mV
1.345ns   92mV       473.3mV    13.62mV
1.722ns   18.12mV    454mV      3.769mV
2.165ns   5.451mV    61.95mV    939.8uV
2.77ns    1.329mV    8.238mV    216.4uV
20ns      1.918nV    -61.27nV   -105.9nV
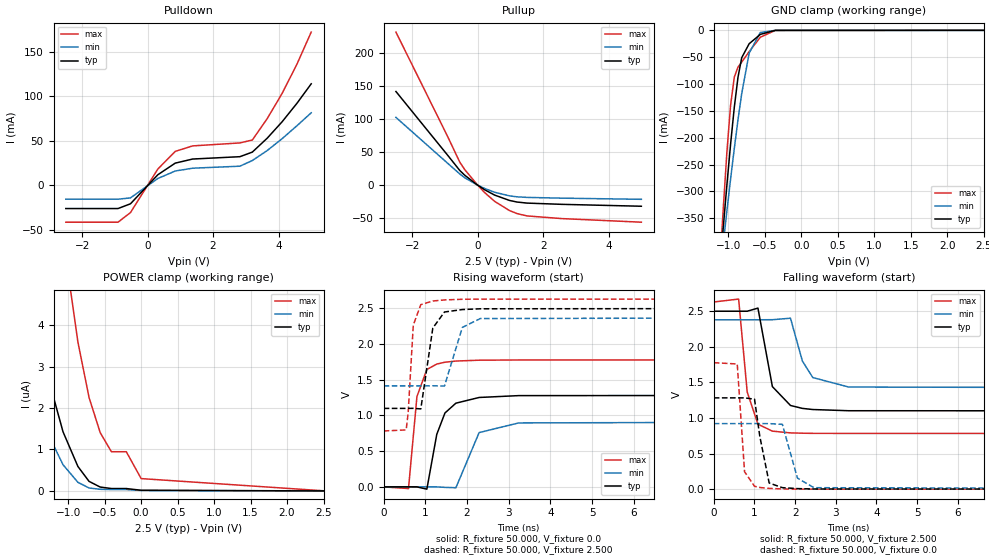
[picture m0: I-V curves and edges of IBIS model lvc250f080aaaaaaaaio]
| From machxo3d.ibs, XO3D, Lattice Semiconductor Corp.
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|   Model lvc250f080aaaaaaaaio
[Model] lvc250f080aaaaaaaaio
Model_type I/O
Polarity   Non-Inverting
Enable   Active-Low
Vinl =  0.700V
Vinh =  1.700V
Vmeas =  1.250V
Cref =  0.0F
Rref =  1.000M
Vref =  0.0V
C_comp   4.200pF   3.800pF   7.500pF
[Temperature Range]   25.000   0.105k   -40.000
[Voltage Range]   2.500V   2.380V   2.630V
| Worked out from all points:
|   slope of the pulldown table from 0 to 0.375 V, typ, clamps not added: 27.2 ohm
|   slope of the pullup table from 0 to 0.375 V, typ, clamps not added: 32.5 ohm
|   GND clamp passes 1 mA (typ) near -0.43 V on its own axis
|   rising waveform, R_fixture 50.000, V_fixture 0.0: 20-80 % time 324ps typ, 400ps min, 194ps max; typ from 0 V to 1.28 V
|   rising waveform, R_fixture 50.000, V_fixture 2.500: 20-80 % time 185ps typ, 278ps min, 111ps max; typ from 1.1 V to 2.5 V
|   falling waveform, R_fixture 50.000, V_fixture 2.500: 20-80 % time 303ps typ, 375ps min, 220ps max; typ from 2.5 V to 1.1 V
|   falling waveform, R_fixture 50.000, V_fixture 0.0: 20-80 % time 158ps typ, 244ps min, 103ps max; typ from 1.28 V to 0 V
[Pulldown]
|Voltage   I(typ)   I(min)   I(max)
-2.5V     -26.15mA   -15.63mA   -41.49mA
-904mV    -26.15mA   -15.63mA   -41.49mA
-524mV    -20.82mA   -14.22mA   -30.68mA
312mV     11.8mA     7.606mA    18.2mA
844mV     24.87mA    16.01mA    38.07mA
1.376V    29.47mA    19.17mA    44.23mA
2.82V     32.11mA    21.42mA    47.56mA
3.2V      37.25mA    27.79mA    50.84mA
3.656V    52.93mA    39.03mA    74.92mA
4.112V    71.4mA     52.39mA    103.3mA
4.568V    92.3mA     67.03mA    136.4mA
5V        114mA      81.44mA    172.1mA
[Pullup]
|Voltage   I(typ)   I(min)   I(max)
-2.5V     142.3mA    103mA      232.5mA
-928mV    46.08mA    33.71mA    74.78mA
-548mV    22.36mA    17.09mA    34.99mA
-396mV    15.13mA    11.26mA    23.61mA
-16mV     565.7uA    408.1uA    908.9uA
212mV     -6.926mA   -4.965mA   -11.2mA
516mV     -14.99mA   -10.65mA   -24.49mA
972mV     -23.14mA   -16.17mA   -38.54mA
1.2V      -25.53mA   -17.64mA   -43.04mA
1.504V    -27.14mA   -18.5mA    -46.6mA
2.568V    -29.04mA   -19.65mA   -50.67mA
5V        -31.92mA   -21.41mA   -56.14mA
[GND_clamp]
|Voltage   I(typ)   I(min)   I(max)
-2.5V     -2.99A     -2.35A     -4.091A
-1.123V   -455.1mA   -463.2mA   -453.6mA
-1.072V   -370.5mA   -399.5mA   -336.3mA
-1.021V   -289.1mA   -337.4mA   -228.5mA
-970mV    -212.6mA   -277.3mA   -139.9mA
-919mV    -143.6mA   -220.1mA   -87.34mA
-868mV    -87.35mA   -166.5mA   -68.39mA
-817mV    -50.9mA    -117.8mA   -59.07mA
-715mV    -24.94mA   -42.34mA   -39.63mA
-562mV    -7.547mA   -4.077mA   -12.85mA
-358mV    -114uA     -53.77uA   -172.8uA
2.5V      0A         0A         0A
[POWER_clamp]
|Voltage   I(typ)   I(min)   I(max)
-2.5V     16.57uA    10.06uA    44.17uA
-2.09V    10.8uA     6.285uA    30.12uA
-1.682V   6.109uA    3.358uA    18.45uA
-1.376V   3.384uA    1.736uA    11.44uA
-1.07V    1.428uA    632.8nA    6.128uA
-866mV    590.6nA    207.8nA    3.594uA
-713mV    230.3nA    70.47nA    2.252uA
-560mV    93.25nA    38.98nA    1.406uA
-407mV    57.68nA    33.36nA    946nA
-203mV    57.68nA    32.35nA    946nA
1mV       16.06nA    10.58nA    297.5nA
2.5V      0A         0A         3.667nA
[Ramp]
| variable   typ   min   max
dV/dt_r   0.770/0.324n   0.553/0.395n   1.066/0.189n
dV/dt_f   0.841/0.306n   0.579/0.364n   1.108/0.220n
R_load = 50.000
[Rising Waveform]
R_fixture= 50.000
V_fixture= 0.0
V_fixture_min= 0.0
V_fixture_max= 0.0
|time   V(typ)   V(min)   V(max)
0s        6.216nV    45.16nV    21.49nV
596ps     44.53uV    -121.4nV   -23.36mV
798ps     -158.4uV   -121.4nV   1.265V
1.036ns   -31.92mV   24.65uV    1.644V
1.274ns   735.9mV    19.4uV     1.72V
1.47ns    1.035V     -6.722mV   1.746V
1.732ns   1.172V     -12.04mV   1.762V
2.289ns   1.252V     760.1mV    1.774V
3.237ns   1.278V     895.7mV    1.777V
20ns      1.283V     921.3mV    1.777V
[Rising Waveform]
R_fixture= 50.000
V_fixture= 2.500
V_fixture_min= 2.380
V_fixture_max= 2.630
|time   V(typ)   V(min)   V(max)
0s        1.099V     1.414V     783mV
540ps     1.099V     1.414V     797.6mV
588ps     1.099V     1.414V     1.04V
711ps     1.1V       1.414V     2.266V
891ps     1.092V     1.414V     2.552V
1.179ns   2.224V     1.416V     2.603V
1.459ns   2.449V     1.413V     2.618V
1.887ns   2.483V     2.233V     2.627V
2.317ns   2.494V     2.357V     2.629V
20ns      2.5V       2.38V      2.63V
[Falling Waveform]
R_fixture= 50.000
V_fixture= 2.500
V_fixture_min= 2.380
V_fixture_max= 2.630
|time   V(typ)   V(min)   V(max)
0s        2.5V       2.38V      2.63V
611ps     2.5V       2.38V      2.671V
822ps     2.5V       2.38V      1.365V
1.086ns   2.544V     2.38V      913.3mV
1.441ns   1.441V     2.381V     815.3mV
1.886ns   1.176V     2.402V     790.6mV
2.178ns   1.135V     1.801V     786.3mV
2.435ns   1.119V     1.568V     784mV
3.319ns   1.102V     1.435V     783.1mV
20ns      1.099V     1.414V     782.9mV
[Falling Waveform]
R_fixture= 50.000
V_fixture= 0.0
V_fixture_min= 0.0
V_fixture_max= 0.0
|time   V(typ)   V(min)   V(max)
0s        1.283V     921.3mV    1.777V
577ps     1.283V     921.2mV    1.759V
757ps     1.283V     921.3mV    244.5mV
1.002ns   1.264V     921.3mV    40.9mV
1.132ns   741.5mV    921.3mV    23.61mV
1.362ns   86.49mV    921.3mV    10.57mV
1.686ns   21.25mV    910.8mV    3.315mV
2.057ns   7.846mV    155.8mV    903.3uV
2.463ns   2.617mV    20.68mV    292.7uV
20ns      67.74nV    -41.98nV   -218.8nV
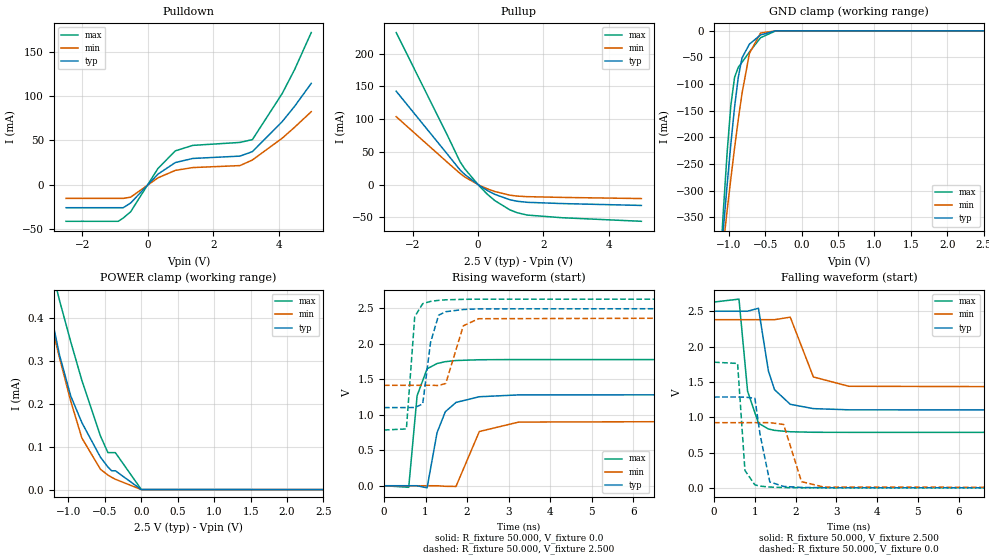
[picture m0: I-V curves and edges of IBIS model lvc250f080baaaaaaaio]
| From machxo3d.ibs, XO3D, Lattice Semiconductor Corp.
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|   Model lvc250f080baaaaaaaio
[Model] lvc250f080baaaaaaaio
Model_type I/O
Polarity   Non-Inverting
Enable   Active-Low
Vinl =  0.700V
Vinh =  1.700V
Vmeas =  1.250V
Cref =  0.0F
Rref =  1.000M
Vref =  0.0V
C_comp   4.200pF   3.800pF   7.500pF
[Temperature Range]   25.000   0.105k   -40.000
[Voltage Range]   2.500V   2.380V   2.630V
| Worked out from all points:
|   slope of the pulldown table from 0 to 0.375 V, typ, clamps not added: 27.2 ohm
|   slope of the pullup table from 0 to 0.375 V, typ, clamps not added: 32.5 ohm
|   GND clamp passes 1 mA (typ) near -0.43 V on its own axis
|   POWER clamp passes 1 mA (typ) near -1.90 V on its own axis
|   rising waveform, R_fixture 50.000, V_fixture 0.0: 20-80 % time 323ps typ, 400ps min, 193ps max; typ from 0.001 V to 1.29 V
|   rising waveform, R_fixture 50.000, V_fixture 2.500: 20-80 % time 185ps typ, 277ps min, 111ps max; typ from 1.1 V to 2.5 V
|   falling waveform, R_fixture 50.000, V_fixture 2.500: 20-80 % time 305ps typ, 376ps min, 221ps max; typ from 2.5 V to 1.1 V
|   falling waveform, R_fixture 50.000, V_fixture 0.0: 20-80 % time 158ps typ, 245ps min, 104ps max; typ from 1.29 V to 0.001 V
[Pulldown]
|Voltage   I(typ)   I(min)   I(max)
-2.5V     -26.15mA   -15.63mA   -41.49mA
-904mV    -26.15mA   -15.63mA   -41.49mA
-752mV    -26.15mA   -15.63mA   -37.84mA
-524mV    -20.82mA   -14.22mA   -30.68mA
312mV     11.8mA     7.606mA    18.2mA
844mV     24.87mA    16.01mA    38.07mA
1.376V    29.47mA    19.17mA    44.23mA
2.82V     32.11mA    21.41mA    47.56mA
3.2V      37.19mA    27.74mA    50.76mA
4.112V    71.07mA    52.35mA    102.8mA
4.492V    88.4mA     64.72mA    129.9mA
5V        114.2mA    82.27mA    171.6mA
[Pullup]
|Voltage   I(typ)   I(min)   I(max)
-2.5V     142.5mA    103.6mA    232.1mA
-928mV    45.99mA    33.64mA    74.57mA
-548mV    22.33mA    17.08mA    34.93mA
-396mV    15.12mA    11.25mA    23.6mA
60mV      -2.071mA   -1.49mA    -3.336mA
288mV     -9.146mA   -6.543mA   -14.83mA
516mV     -14.99mA   -10.65mA   -24.49mA
972mV     -23.14mA   -16.17mA   -38.54mA
1.2V      -25.53mA   -17.64mA   -43.04mA
1.504V    -27.14mA   -18.5mA    -46.6mA
2.568V    -29.04mA   -19.65mA   -50.67mA
5V        -31.92mA   -21.41mA   -56.14mA
[GND_clamp]
|Voltage   I(typ)   I(min)   I(max)
-2.5V     -2.99A     -2.35A     -4.091A
-1.123V   -455.1mA   -463.2mA   -453.7mA
-1.072V   -370.5mA   -399.5mA   -336.3mA
-1.021V   -289.2mA   -337.4mA   -228.6mA
-970mV    -212.6mA   -277.4mA   -140mA
-919mV    -143.6mA   -220.1mA   -87.39mA
-868mV    -87.38mA   -166.5mA   -68.44mA
-817mV    -50.93mA   -117.8mA   -59.12mA
-715mV    -24.98mA   -42.36mA   -39.69mA
-562mV    -7.596mA   -4.111mA   -12.93mA
-358mV    -193.4uA   -101.2uA   -309.3uA
2.5V      13.17nA    0A         -19.29uA
[POWER_clamp]
|Voltage   I(typ)   I(min)   I(max)
-2.5V     1.538mA    1.365mA    2.125mA
-1.325V   482.6uA    450.2uA    591.5uA
-1.274V   438.4uA    413.8uA    546.6uA
-1.121V   313.5uA    307.1uA    441uA
-968mV    218.6uA    206.5uA    345.2uA
-815mV    156.3uA    120.3uA    254.8uA
-560mV    75.6uA     47.55uA    125.2uA
-458mV    52.75uA    33.88uA    86.35uA
-407mV    44.01uA    28.68uA    86.35uA
-356mV    44.01uA    24.21uA    86.35uA
1mV       0A         0A         141nA
2.5V      0A         0A         0A
[Ramp]
| variable   typ   min   max
dV/dt_r   0.771/0.323n   0.553/0.395n   1.066/0.188n
dV/dt_f   0.839/0.307n   0.578/0.365n   1.106/0.221n
R_load = 50.000
[Rising Waveform]
R_fixture= 50.000
V_fixture= 0.0
V_fixture_min= 0.0
V_fixture_max= 0.0
|time   V(typ)   V(min)   V(max)
0s        1.328mV    1.004mV    1.82mV
596ps     1.372mV    1.003mV    -20.98mV
798ps     1.152mV    1.003mV    1.27V
1.038ns   -28.65mV   1.155mV    1.648V
1.278ns   748.9mV    1.03mV     1.723V
1.477ns   1.044V     -6.899mV   1.749V
1.734ns   1.175V     -8.827mV   1.765V
2.295ns   1.255V     764.8mV    1.776V
3.245ns   1.281V     898.2mV    1.779V
20ns      1.286V     923.4mV    1.779V
[Rising Waveform]
R_fixture= 50.000
V_fixture= 2.500
V_fixture_min= 2.380
V_fixture_max= 2.630
|time   V(typ)   V(min)   V(max)
0s        1.102V     1.416V     786.3mV
540ps     1.102V     1.416V     801.2mV
741ps     1.103V     1.416V     2.383V
933ps     1.153V     1.416V     2.566V
1.121ns   2.019V     1.417V     2.598V
1.316ns   2.404V     1.413V     2.613V
1.488ns   2.453V     1.443V     2.62V
1.91ns    2.484V     2.254V     2.627V
2.277ns   2.493V     2.354V     2.629V
20ns      2.5V       2.38V      2.63V
[Falling Waveform]
R_fixture= 50.000
V_fixture= 2.500
V_fixture_min= 2.380
V_fixture_max= 2.630
|time   V(typ)   V(min)   V(max)
0s        2.5V       2.38V      2.63V
611ps     2.5V       2.38V      2.671V
822ps     2.5V       2.38V      1.368V
1.089ns   2.542V     2.38V      916.1mV
1.333ns   1.655V     2.38V      833.6mV
1.483ns   1.39V      2.38V      814.5mV
1.869ns   1.183V     2.416V     794.7mV
2.436ns   1.122V     1.57V      787.3mV
3.308ns   1.105V     1.438V     786.4mV
20ns      1.102V     1.416V     786.1mV
[Falling Waveform]
R_fixture= 50.000
V_fixture= 0.0
V_fixture_min= 0.0
V_fixture_max= 0.0
|time   V(typ)   V(min)   V(max)
0s        1.286V     923.4mV    1.779V
577ps     1.286V     923.3mV    1.761V
757ps     1.285V     923.5mV    247.8mV
1.001ns   1.268V     923.5mV    43.03mV
1.132ns   744.8mV    923.5mV    25.35mV
1.367ns   85.32mV    923.4mV    12.27mV
1.706ns   21.41mV    897.8mV    5.085mV
2.145ns   7.163mV    88.91mV    2.513mV
2.692ns   2.829mV    12.15mV    2.01mV
20ns      1.328mV    1.004mV    1.82mV
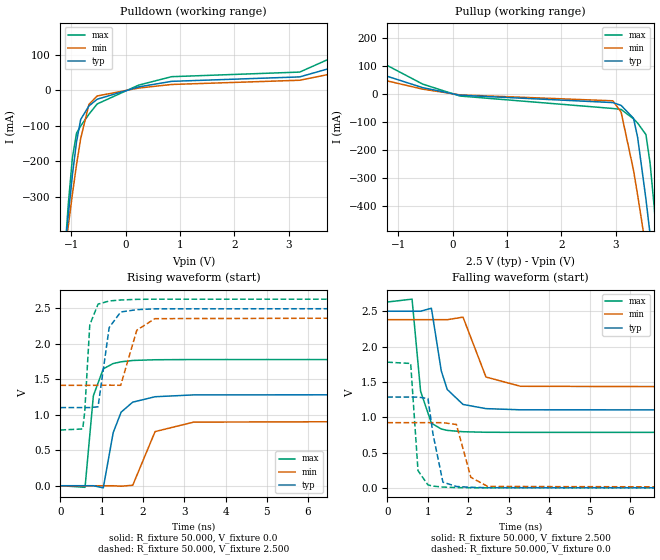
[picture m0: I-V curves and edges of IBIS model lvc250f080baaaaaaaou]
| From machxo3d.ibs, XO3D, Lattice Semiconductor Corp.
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|   Model lvc250f080baaaaaaaou
[Model] lvc250f080baaaaaaaou
Model_type Output
Polarity   Non-Inverting
Enable   Active-High
Vmeas =  1.250V
Cref =  0.0F
Rref =  1.000M
Vref =  0.0V
C_comp   4.200pF   3.800pF   7.500pF
[Temperature Range]   25.000   0.105k   -40.000
[Voltage Range]   2.500V   2.380V   2.630V
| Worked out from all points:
|   slope of the pulldown table from 0 to 0.375 V, typ, clamps not added: 27.2 ohm
|   slope of the pullup table from 0 to 0.375 V, typ, clamps not added: 32.5 ohm
|   rising waveform, R_fixture 50.000, V_fixture 0.0: 20-80 % time 324ps typ, 400ps min, 193ps max; typ from 0.001 V to 1.29 V
|   rising waveform, R_fixture 50.000, V_fixture 2.500: 20-80 % time 185ps typ, 277ps min, 111ps max; typ from 1.1 V to 2.5 V
|   falling waveform, R_fixture 50.000, V_fixture 2.500: 20-80 % time 305ps typ, 376ps min, 221ps max; typ from 2.5 V to 1.1 V
|   falling waveform, R_fixture 50.000, V_fixture 0.0: 20-80 % time 158ps typ, 244ps min, 104ps max; typ from 1.29 V to 0.001 V
[Pulldown]
|Voltage   I(typ)   I(min)   I(max)
-2.5V     -2.991A    -2.35A     -4.092A
-1.132V   -475mA     -476.9mA   -485.1mA
-1.056V   -351.6mA   -382.8mA   -321.6mA
-980mV    -239mA     -292.8mA   -190.2mA
-904mV    -145.4mA   -209.4mA   -121mA
-828mV    -82.59mA   -136.3mA   -101mA
-676mV    -44.45mA   -39.98mA   -67.89mA
-524mV    -25.55mA   -16.41mA   -38.81mA
236mV     9.132mA    5.891mA    14.06mA
844mV     24.79mA    15.96mA    37.92mA
3.2V      37.3mA     27.87mA    50.89mA
5V        115.7mA    83.75mA    173.5mA
[Pullup]
|Voltage   I(typ)   I(min)   I(max)
-2.5V     144mA      105mA      234.2mA
-548mV    22.4mA     17.12mA    35.05mA
136mV     -4.58mA    -3.289mA   -7.395mA
2.948V    -30.81mA   -24.5mA    -51.86mA
3.1V      -40.87mA   -65.27mA   -55.33mA
3.328V    -86.97mA   -272.6mA   -88.94mA
3.404V    -155.7mA   -361.4mA   -104.1mA
3.556V    -375mA     -551.2mA   -145.2mA
3.632V    -500.8mA   -649.9mA   -245.9mA
3.708V    -631.5mA   -750.2mA   -403.3mA
3.784V    -765.1mA   -851.7mA   -581.6mA
5V        -3.022A    -2.541A    -3.796A
[Ramp]
| variable   typ   min   max
dV/dt_r   0.771/0.323n   0.553/0.395n   1.066/0.188n
dV/dt_f   0.839/0.307n   0.578/0.365n   1.106/0.221n
R_load = 50.000
[Rising Waveform]
R_fixture= 50.000
V_fixture= 0.0
V_fixture_min= 0.0
V_fixture_max= 0.0
|time   V(typ)   V(min)   V(max)
0s        1.328mV    1.004mV    1.82mV
596ps     1.37mV     999.9uV    -20.97mV
798ps     1.164mV    999.9uV    1.27V
1.038ns   -28.65mV   1.099mV    1.648V
1.278ns   748.9mV    1.029mV    1.723V
1.47ns    1.038V     -5.712mV   1.747V
1.752ns   1.179V     8.386mV    1.766V
2.293ns   1.255V     764mV      1.776V
3.228ns   1.281V     897.5mV    1.779V
20ns      1.286V     923.4mV    1.779V
[Rising Waveform]
R_fixture= 50.000
V_fixture= 2.500
V_fixture_min= 2.380
V_fixture_max= 2.630
|time   V(typ)   V(min)   V(max)
0s        1.102V     1.416V     786.3mV
540ps     1.102V     1.416V     801.2mV
588ps     1.102V     1.416V     1.044V
711ps     1.103V     1.416V     2.268V
911ps     1.113V     1.416V     2.559V
1.181ns   2.23V      1.418V     2.604V
1.46ns    2.449V     1.416V     2.618V
1.85ns    2.482V     2.192V     2.627V
2.287ns   2.493V     2.355V     2.629V
20ns      2.5V       2.38V      2.63V
[Falling Waveform]
R_fixture= 50.000
V_fixture= 2.500
V_fixture_min= 2.380
V_fixture_max= 2.630
|time   V(typ)   V(min)   V(max)
0s        2.5V       2.38V      2.63V
611ps     2.5V       2.38V      2.671V
822ps     2.5V       2.38V      1.368V
1.089ns   2.542V     2.38V      916mV
1.333ns   1.655V     2.38V      833.6mV
1.48ns    1.393V     2.38V      814.2mV
1.87ns    1.181V     2.416V     795.2mV
2.437ns   1.122V     1.569V     787.4mV
3.291ns   1.105V     1.438V     786.3mV
20ns      1.102V     1.416V     786.2mV
[Falling Waveform]
R_fixture= 50.000
V_fixture= 0.0
V_fixture_min= 0.0
V_fixture_max= 0.0
|time   V(typ)   V(min)   V(max)
0s        1.286V     923.4mV    1.779V
577ps     1.286V     923.3mV    1.761V
758ps     1.285V     923.5mV    244.6mV
1.004ns   1.265V     923.5mV    42.09mV
1.128ns   763.1mV    923.5mV    25.66mV
1.373ns   81.92mV    923.4mV    12.16mV
1.706ns   20.53mV    897.8mV    5.028mV
2.064ns   8.674mV    150mV      2.871mV
2.481ns   3.95mV     20.52mV    2.081mV
20ns      1.328mV    1.004mV    1.819mV
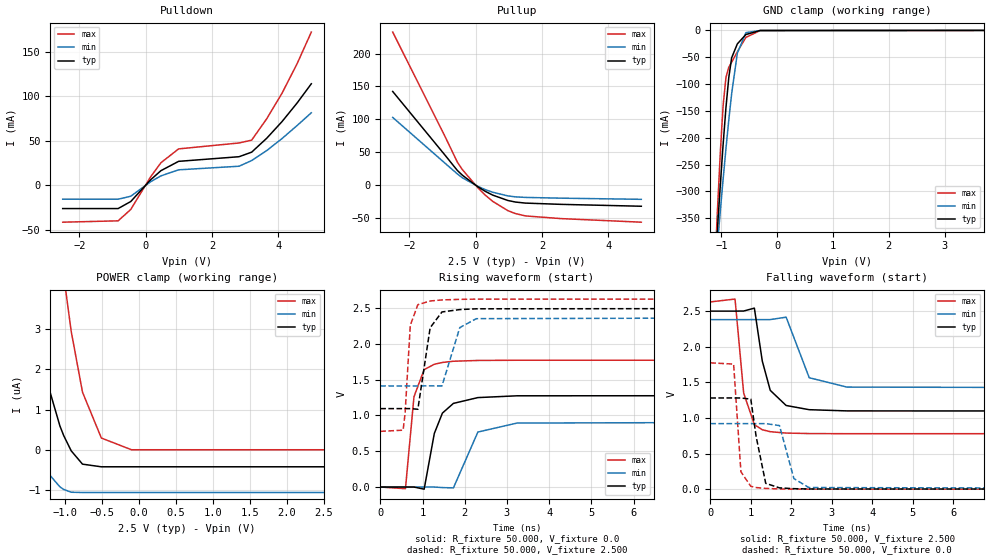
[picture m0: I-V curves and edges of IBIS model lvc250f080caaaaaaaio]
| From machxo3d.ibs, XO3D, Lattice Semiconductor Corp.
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|   Model lvc250f080caaaaaaaio
[Model] lvc250f080caaaaaaaio
Model_type I/O
Polarity   Non-Inverting
Enable   Active-Low
Vinl =  0.700V
Vinh =  1.700V
Vmeas =  1.250V
Cref =  0.0F
Rref =  1.000M
Vref =  0.0V
C_comp   4.200pF   3.800pF   7.500pF
[Temperature Range]   25.000   0.105k   -40.000
[Voltage Range]   2.500V   2.380V   2.630V
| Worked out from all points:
|   slope of the pulldown table from 0 to 0.375 V, typ, clamps not added: 27.2 ohm
|   slope of the pullup table from 0 to 0.375 V, typ, clamps not added: 32.5 ohm
|   GND clamp passes 1 mA (typ) near -0.43 V on its own axis
|   rising waveform, R_fixture 50.000, V_fixture 0.0: 20-80 % time 325ps typ, 401ps min, 192ps max; typ from 0 V to 1.28 V
|   rising waveform, R_fixture 50.000, V_fixture 2.500: 20-80 % time 185ps typ, 278ps min, 110ps max; typ from 1.1 V to 2.5 V
|   falling waveform, R_fixture 50.000, V_fixture 2.500: 20-80 % time 304ps typ, 376ps min, 220ps max; typ from 2.5 V to 1.09 V
|   falling waveform, R_fixture 50.000, V_fixture 0.0: 20-80 % time 157ps typ, 242ps min, 103ps max; typ from 1.28 V to 0 V
[Pulldown]
|Voltage   I(typ)   I(min)   I(max)
-2.5V     -26.15mA   -15.63mA   -41.49mA
-828mV    -26.15mA   -15.63mA   -39.97mA
-448mV    -18.28mA   -12.33mA   -27.2mA
160mV     6.444mA    4.153mA    9.94mA
464mV     16.44mA    10.59mA    25.34mA
996mV     26.9mA     17.37mA    40.9mA
2.82V     32.11mA    21.41mA    47.56mA
3.2V      37.22mA    27.79mA    50.73mA
3.656V    52.92mA    39.04mA    74.84mA
4.112V    71.41mA    52.41mA    103.2mA
4.568V    92.33mA    67.06mA    136.4mA
5V        114.1mA    81.49mA    172.2mA
[Pullup]
|Voltage   I(typ)   I(min)   I(max)
-2.5V     142.4mA    103mA      232.6mA
-928mV    46.07mA    33.71mA    74.7mA
-548mV    22.33mA    17.08mA    34.9mA
-396mV    15.12mA    11.25mA    23.6mA
60mV      -2.071mA   -1.49mA    -3.336mA
288mV     -9.146mA   -6.543mA   -14.83mA
516mV     -14.99mA   -10.65mA   -24.49mA
972mV     -23.14mA   -16.17mA   -38.54mA
1.2V      -25.53mA   -17.64mA   -43.04mA
1.504V    -27.14mA   -18.5mA    -46.6mA
2.568V    -29.04mA   -19.65mA   -50.67mA
5V        -31.92mA   -21.41mA   -56.14mA
[GND_clamp]
|Voltage   I(typ)   I(min)   I(max)
-2.5V     -2.99A     -2.35A     -4.091A
-1.123V   -455.1mA   -463.2mA   -453.7mA
-1.072V   -370.5mA   -399.5mA   -336.3mA
-1.021V   -289.2mA   -337.4mA   -228.6mA
-970mV    -212.6mA   -277.4mA   -140mA
-919mV    -143.6mA   -220.1mA   -87.4mA
-868mV    -87.39mA   -166.5mA   -68.45mA
-817mV    -50.94mA   -117.8mA   -59.13mA
-715mV    -24.99mA   -42.37mA   -39.7mA
-562mV    -7.608mA   -4.125mA   -12.95mA
-307mV    -97.66uA   -51.76uA   -173.8uA
5V        114uA      49.34uA    266.8uA
[POWER_clamp]
|Voltage   I(typ)   I(min)   I(max)
-2.5V     22.27uA    8.76uA     64.97uA
-2.141V   14.03uA    4.838uA    43.67uA
-1.835V   8.45uA     2.288uA    28.47uA
-1.58V    4.901uA    735.9nA    18.31uA
-1.274V   1.887uA    -485.7nA   9.321uA
-1.07V    594.4nA    -924nA     5.173uA
-1.019V   355.1nA    -987.6nA   4.351uA
-917mV    -26.39nA   -1.058uA   2.951uA
-764mV    -358.7nA   -1.065uA   1.434uA
-509mV    -424.8nA   -1.065uA   291.6nA
-101mV    -424.8nA   -1.065uA   0A
2.5V      -424.8nA   -1.065uA   0A
[Ramp]
| variable   typ   min   max
dV/dt_r   0.768/0.324n   0.552/0.395n   1.063/0.189n
dV/dt_f   0.842/0.305n   0.580/0.364n   1.109/0.219n
R_load = 50.000
[Rising Waveform]
R_fixture= 50.000
V_fixture= 0.0
V_fixture_min= 0.0
V_fixture_max= 0.0
|time   V(typ)   V(min)   V(max)
0s        6.01nV     44.68nV    20.69nV
596ps     44.49uV    -155.8nV   -23.3mV
798ps     -161.8uV   -155.8nV   1.262V
1.039ns   -29.88mV   24.63uV    1.641V
1.28ns    749.3mV    17.57uV    1.716V
1.471ns   1.033V     -7.906mV   1.741V
1.732ns   1.169V     -11.99mV   1.758V
2.311ns   1.25V      768.3mV    1.769V
3.238ns   1.275V     894.2mV    1.772V
20ns      1.279V     919.6mV    1.772V
[Rising Waveform]
R_fixture= 50.000
V_fixture= 2.500
V_fixture_min= 2.380
V_fixture_max= 2.630
|time   V(typ)   V(min)   V(max)
0s        1.096V     1.413V     778.2mV
541ps     1.096V     1.413V     794.5mV
588ps     1.096V     1.413V     1.033V
711ps     1.096V     1.413V     2.261V
890ps     1.087V     1.413V     2.549V
1.181ns   2.226V     1.414V     2.6V
1.461ns   2.447V     1.413V     2.615V
1.883ns   2.48V      2.228V     2.623V
2.274ns   2.491V     2.353V     2.626V
20ns      2.498V     2.379V     2.627V
[Falling Waveform]
R_fixture= 50.000
V_fixture= 2.500
V_fixture_min= 2.380
V_fixture_max= 2.630
|time   V(typ)   V(min)   V(max)
0s        2.498V     2.379V     2.627V
611ps     2.498V     2.379V     2.667V
824ps     2.499V     2.379V     1.349V
1.088ns   2.54V      2.379V     905.1mV
1.283ns   1.798V     2.379V     833.6mV
1.48ns    1.386V     2.379V     806.3mV
1.872ns   1.174V     2.413V     787.2mV
2.442ns   1.115V     1.563V     780.1mV
3.374ns   1.098V     1.432V     778.2mV
20ns      1.095V     1.413V     778.2mV
[Falling Waveform]
R_fixture= 50.000
V_fixture= 0.0
V_fixture_min= 0.0
V_fixture_max= 0.0
|time   V(typ)   V(min)   V(max)
0s        1.279V     919.6mV    1.772V
576ps     1.28V      919.5mV    1.755V
756ps     1.279V     919.7mV    243.3mV
1ns       1.263V     919.7mV    40.13mV
1.132ns   737.5mV    919.7mV    22.9mV
1.368ns   81.82mV    919.6mV    10.11mV
1.708ns   18.28mV    892.1mV    3.089mV
2.063ns   7.03mV     148.5mV    1.009mV
2.43ns    2.771mV    22.71mV    351uV
20ns      -130.7nV   -85.29nV   -377.9nV
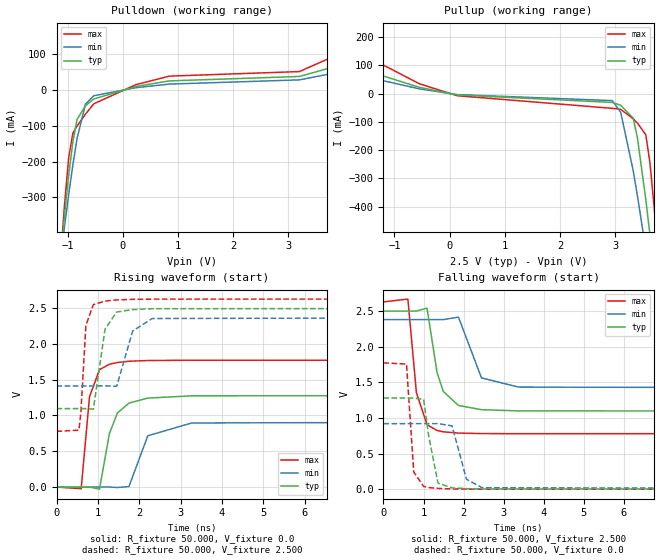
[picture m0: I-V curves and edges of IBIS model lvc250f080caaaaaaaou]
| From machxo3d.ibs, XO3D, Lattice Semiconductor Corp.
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|   Model lvc250f080caaaaaaaou
[Model] lvc250f080caaaaaaaou
Model_type Output
Polarity   Non-Inverting
Enable   Active-High
Vmeas =  1.250V
Cref =  0.0F
Rref =  1.000M
Vref =  0.0V
C_comp   4.200pF   3.800pF   7.500pF
[Temperature Range]   25.000   0.105k   -40.000
[Voltage Range]   2.500V   2.380V   2.630V
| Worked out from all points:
|   slope of the pulldown table from 0 to 0.375 V, typ, clamps not added: 27 ohm
|   slope of the pullup table from 0 to 0.375 V, typ, clamps not added: 32.5 ohm
|   rising waveform, R_fixture 50.000, V_fixture 0.0: 20-80 % time 325ps typ, 401ps min, 193ps max; typ from 0 V to 1.28 V
|   rising waveform, R_fixture 50.000, V_fixture 2.500: 20-80 % time 185ps typ, 277ps min, 110ps max; typ from 1.1 V to 2.5 V
|   falling waveform, R_fixture 50.000, V_fixture 2.500: 20-80 % time 303ps typ, 376ps min, 220ps max; typ from 2.5 V to 1.09 V
|   falling waveform, R_fixture 50.000, V_fixture 0.0: 20-80 % time 158ps typ, 243ps min, 103ps max; typ from 1.28 V to 0 V
[Pulldown]
|Voltage   I(typ)   I(min)   I(max)
-2.5V     -2.991A    -2.35A     -4.092A
-1.132V   -475mA     -476.9mA   -485.2mA
-1.056V   -351.6mA   -382.8mA   -321.7mA
-980mV    -239mA     -292.8mA   -190.2mA
-904mV    -145.4mA   -209.4mA   -121mA
-828mV    -82.6mA    -136.3mA   -101mA
-676mV    -44.46mA   -39.99mA   -67.9mA
-524mV    -25.56mA   -16.43mA   -38.82mA
236mV     9.262mA    5.959mA    14.32mA
844mV     24.96mA    16.05mA    38.3mA
3.2V      37.32mA    27.83mA    50.99mA
5V        114.2mA    81.55mA    172.5mA
[Pullup]
|Voltage   I(typ)   I(min)   I(max)
-2.5V     142.5mA    103.1mA    233mA
-548mV    22.43mA    17.12mA    35.15mA
136mV     -4.464mA   -3.242mA   -7.127mA
2.948V    -30.82mA   -24.51mA   -51.85mA
3.1V      -40.88mA   -65.28mA   -55.33mA
3.328V    -86.97mA   -272.6mA   -88.95mA
3.404V    -155.7mA   -361.4mA   -104.1mA
3.556V    -375mA     -551.2mA   -145.3mA
3.632V    -500.8mA   -649.9mA   -245.9mA
3.708V    -631.5mA   -750.2mA   -403.3mA
3.784V    -765.1mA   -851.7mA   -581.6mA
5V        -3.022A    -2.541A    -3.796A
[Ramp]
| variable   typ   min   max
dV/dt_r   0.768/0.324n   0.552/0.395n   1.063/0.189n
dV/dt_f   0.842/0.305n   0.580/0.364n   1.109/0.219n
R_load = 50.000
[Rising Waveform]
R_fixture= 50.000
V_fixture= 0.0
V_fixture_min= 0.0
V_fixture_max= 0.0
|time   V(typ)   V(min)   V(max)
0s        6.01nV     44.68nV    20.69nV
596ps     41.6uV     -3.088uV   -23.3mV
798ps     -160.4uV   -3.088uV   1.262V
1.039ns   -29.88mV   21.18uV    1.64V
1.28ns    749.3mV    29.94uV    1.716V
1.471ns   1.033V     -7.047mV   1.74V
1.752ns   1.173V     6.728mV    1.758V
2.208ns   1.243V     715.9mV    1.768V
3.27ns    1.275V     895.4mV    1.772V
20ns      1.279V     919.6mV    1.772V
[Rising Waveform]
R_fixture= 50.000
V_fixture= 2.500
V_fixture_min= 2.380
V_fixture_max= 2.630
|time   V(typ)   V(min)   V(max)
0s        1.096V     1.413V     778.2mV
541ps     1.096V     1.413V     794.5mV
588ps     1.096V     1.413V     1.033V
711ps     1.096V     1.413V     2.261V
891ps     1.088V     1.413V     2.549V
1.174ns   2.208V     1.414V     2.599V
1.455ns   2.446V     1.409V     2.615V
1.842ns   2.48V      2.18V      2.623V
2.313ns   2.492V     2.355V     2.626V
20ns      2.498V     2.379V     2.627V
[Falling Waveform]
R_fixture= 50.000
V_fixture= 2.500
V_fixture_min= 2.380
V_fixture_max= 2.630
|time   V(typ)   V(min)   V(max)
0s        2.498V     2.379V     2.627V
611ps     2.498V     2.379V     2.667V
824ps     2.499V     2.379V     1.349V
1.088ns   2.54V      2.379V     905.1mV
1.337ns   1.639V     2.379V     823.5mV
1.492ns   1.372V     2.379V     804.5mV
1.872ns   1.174V     2.413V     787mV
2.446ns   1.115V     1.561V     780mV
3.371ns   1.098V     1.432V     778.3mV
20ns      1.095V     1.413V     778.1mV
[Falling Waveform]
R_fixture= 50.000
V_fixture= 0.0
V_fixture_min= 0.0
V_fixture_max= 0.0
|time   V(typ)   V(min)   V(max)
0s        1.279V     919.6mV    1.772V
576ps     1.279V     919.6mV    1.755V
757ps     1.279V     919.7mV    240.1mV
1.004ns   1.258V     919.7mV    38.03mV
1.132ns   737.5mV    919.7mV    22.84mV
1.363ns   84.43mV    919.6mV    10.49mV
1.712ns   18.47mV    887.9mV    2.883mV
2.072ns   7.463mV    139.6mV    877uV
2.463ns   2.682mV    20.37mV    272uV
20ns      29.05nV    -114.2nV   -345.8nV
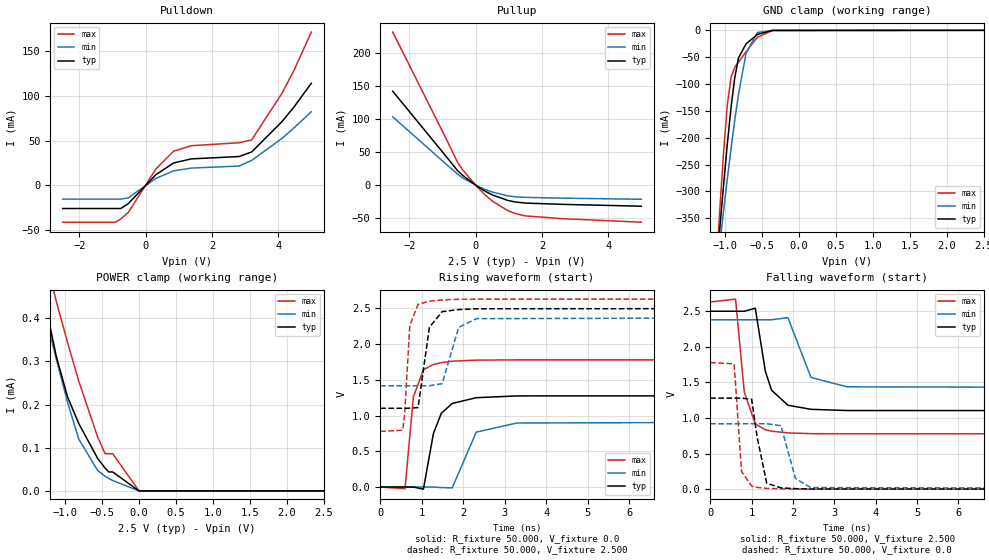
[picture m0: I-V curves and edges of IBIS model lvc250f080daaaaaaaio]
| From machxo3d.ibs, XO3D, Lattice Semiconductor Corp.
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|   Model lvc250f080daaaaaaaio
[Model] lvc250f080daaaaaaaio
Model_type I/O
Polarity   Non-Inverting
Enable   Active-Low
Vinl =  0.700V
Vinh =  1.700V
Vmeas =  1.250V
Cref =  0.0F
Rref =  1.000M
Vref =  0.0V
C_comp   4.200pF   3.800pF   7.500pF
[Temperature Range]   25.000   0.105k   -40.000
[Voltage Range]   2.500V   2.380V   2.630V
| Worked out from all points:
|   slope of the pulldown table from 0 to 0.375 V, typ, clamps not added: 27.2 ohm
|   slope of the pullup table from 0 to 0.375 V, typ, clamps not added: 32.5 ohm
|   GND clamp passes 1 mA (typ) near -0.43 V on its own axis
|   POWER clamp passes 1 mA (typ) near -1.90 V on its own axis
|   rising waveform, R_fixture 50.000, V_fixture 0.0: 20-80 % time 325ps typ, 401ps min, 195ps max; typ from 0 V to 1.28 V
|   rising waveform, R_fixture 50.000, V_fixture 2.500: 20-80 % time 185ps typ, 279ps min, 111ps max; typ from 1.1 V to 2.5 V
|   falling waveform, R_fixture 50.000, V_fixture 2.500: 20-80 % time 305ps typ, 376ps min, 224ps max; typ from 2.5 V to 1.1 V
|   falling waveform, R_fixture 50.000, V_fixture 0.0: 20-80 % time 158ps typ, 245ps min, 104ps max; typ from 1.28 V to 0 V
[Pulldown]
|Voltage   I(typ)   I(min)   I(max)
-2.5V     -26.15mA   -15.63mA   -41.49mA
-904mV    -26.15mA   -15.63mA   -41.49mA
-752mV    -26.15mA   -15.63mA   -37.84mA
-524mV    -20.82mA   -14.22mA   -30.68mA
312mV     11.8mA     7.606mA    18.2mA
844mV     24.87mA    16.01mA    38.07mA
1.376V    29.47mA    19.17mA    44.23mA
2.82V     32.11mA    21.41mA    47.56mA
3.2V      37.19mA    27.74mA    50.76mA
4.112V    71.07mA    52.35mA    102.8mA
4.492V    88.4mA     64.72mA    129.9mA
5V        114.2mA    82.27mA    171.6mA
[Pullup]
|Voltage   I(typ)   I(min)   I(max)
-2.5V     142.5mA    103.6mA    232.1mA
-928mV    45.99mA    33.64mA    74.57mA
-548mV    22.33mA    17.08mA    34.93mA
-396mV    15.12mA    11.25mA    23.6mA
60mV      -2.071mA   -1.49mA    -3.336mA
288mV     -9.146mA   -6.543mA   -14.83mA
516mV     -14.99mA   -10.65mA   -24.49mA
972mV     -23.14mA   -16.17mA   -38.54mA
1.2V      -25.53mA   -17.64mA   -43.04mA
1.504V    -27.14mA   -18.5mA    -46.6mA
2.568V    -29.04mA   -19.65mA   -50.67mA
5V        -31.92mA   -21.41mA   -56.14mA
[GND_clamp]
|Voltage   I(typ)   I(min)   I(max)
-2.5V     -2.99A     -2.35A     -4.091A
-1.123V   -455.1mA   -463.2mA   -453.7mA
-1.072V   -370.5mA   -399.5mA   -336.3mA
-1.021V   -289.2mA   -337.4mA   -228.6mA
-970mV    -212.6mA   -277.4mA   -140mA
-919mV    -143.6mA   -220.1mA   -87.4mA
-868mV    -87.39mA   -166.5mA   -68.45mA
-817mV    -50.94mA   -117.8mA   -59.13mA
-715mV    -24.99mA   -42.37mA   -39.7mA
-562mV    -7.608mA   -4.125mA   -12.95mA
-358mV    -194.9uA   -98.36uA   -303.6uA
2.5V      13.17nA    0A         -19.29uA
[POWER_clamp]
|Voltage   I(typ)   I(min)   I(max)
-2.5V     1.538mA    1.365mA    2.125mA
-1.325V   482.6uA    450.2uA    591.5uA
-1.274V   438.4uA    413.8uA    546.6uA
-1.121V   313.5uA    307.1uA    441uA
-968mV    218.6uA    206.5uA    345.2uA
-815mV    156.3uA    120.3uA    254.8uA
-560mV    75.6uA     47.55uA    125.2uA
-458mV    52.75uA    33.88uA    86.35uA
-407mV    44.01uA    28.68uA    86.35uA
-356mV    44.01uA    24.21uA    86.35uA
1mV       0A         0A         141nA
2.5V      0A         0A         0A
[Ramp]
| variable   typ   min   max
dV/dt_r   0.768/0.324n   0.552/0.395n   1.068/0.192n
dV/dt_f   0.839/0.307n   0.578/0.365n   1.111/0.224n
R_load = 50.000
[Rising Waveform]
R_fixture= 50.000
V_fixture= 0.0
V_fixture_min= 0.0
V_fixture_max= 0.0
|time   V(typ)   V(min)   V(max)
0s        6.01nV     44.68nV    20.69nV
596ps     44.48uV    -180.6nV   -23.3mV
798ps     -161.8uV   -180.6nV   1.262V
1.039ns   -29.88mV   24.63uV    1.641V
1.28ns    749.3mV    17.58uV    1.716V
1.471ns   1.033V     -7.906mV   1.741V
1.732ns   1.169V     -11.99mV   1.76V
2.311ns   1.25V      768.3mV    1.776V
3.293ns   1.275V     896.3mV    1.779V
20ns      1.279V     919.6mV    1.779V
[Rising Waveform]
R_fixture= 50.000
V_fixture= 2.500
V_fixture_min= 2.380
V_fixture_max= 2.630
|time   V(typ)   V(min)   V(max)
0s        1.102V     1.416V     778.2mV
541ps     1.102V     1.416V     794.5mV
588ps     1.102V     1.416V     1.033V
711ps     1.103V     1.416V     2.261V
910ps     1.112V     1.416V     2.556V
1.183ns   2.235V     1.418V     2.601V
1.49ns    2.454V     1.446V     2.619V
1.889ns   2.483V     2.235V     2.627V
2.319ns   2.494V     2.356V     2.629V
20ns      2.5V       2.38V      2.63V
[Falling Waveform]
R_fixture= 50.000
V_fixture= 2.500
V_fixture_min= 2.380
V_fixture_max= 2.630
|time   V(typ)   V(min)   V(max)
0s        2.5V       2.38V      2.63V
611ps     2.5V       2.38V      2.671V
822ps     2.5V       2.38V      1.368V
1.089ns   2.542V     2.38V      916.1mV
1.333ns   1.655V     2.38V      833.6mV
1.483ns   1.39V      2.38V      814.5mV
1.878ns   1.179V     2.41V      790.4mV
2.436ns   1.122V     1.57V      780mV
3.308ns   1.105V     1.438V     778.3mV
20ns      1.102V     1.416V     778.2mV
[Falling Waveform]
R_fixture= 50.000
V_fixture= 0.0
V_fixture_min= 0.0
V_fixture_max= 0.0
|time   V(typ)   V(min)   V(max)
0s        1.279V     919.6mV    1.779V
577ps     1.28V      919.5mV    1.761V
757ps     1.279V     919.7mV    247.8mV
1.001ns   1.262V     919.7mV    43.03mV
1.132ns   737.5mV    919.7mV    25.35mV
1.365ns   83.54mV    919.6mV    10.82mV
1.708ns   18.28mV    892.1mV    3.593mV
2.063ns   7.03mV     148.5mV    1.074mV
2.43ns    2.771mV    22.71mV    378.7uV
20ns      -130.7nV   -85.29nV   -292.6nV
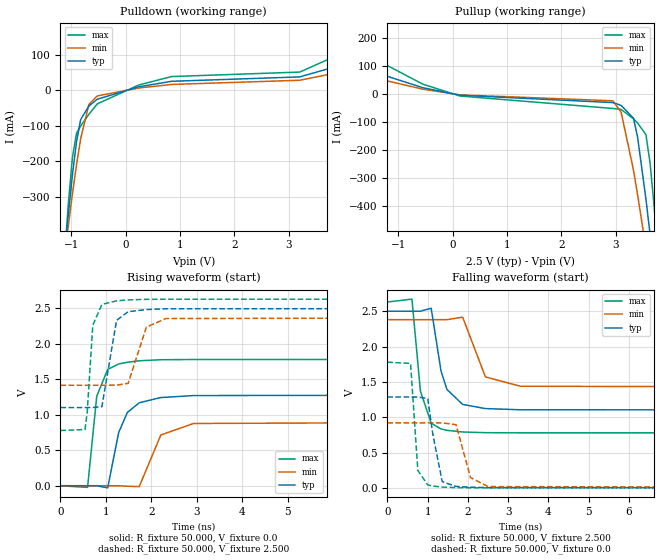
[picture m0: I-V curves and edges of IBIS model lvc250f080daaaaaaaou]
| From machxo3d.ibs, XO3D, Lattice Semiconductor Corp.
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|   Model lvc250f080daaaaaaaou
[Model] lvc250f080daaaaaaaou
Model_type Output
Polarity   Non-Inverting
Enable   Active-High
Vmeas =  1.250V
Cref =  0.0F
Rref =  1.000M
Vref =  0.0V
C_comp   4.200pF   3.800pF   7.500pF
[Temperature Range]   25.000   0.105k   -40.000
[Voltage Range]   2.500V   2.380V   2.630V
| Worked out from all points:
|   slope of the pulldown table from 0 to 0.375 V, typ, clamps not added: 27 ohm
|   slope of the pullup table from 0 to 0.375 V, typ, clamps not added: 32.5 ohm
|   rising waveform, R_fixture 50.000, V_fixture 0.0: 20-80 % time 329ps typ, 401ps min, 195ps max; typ from 0 V to 1.29 V
|   rising waveform, R_fixture 50.000, V_fixture 2.500: 20-80 % time 185ps typ, 278ps min, 111ps max; typ from 1.1 V to 2.5 V
|   falling waveform, R_fixture 50.000, V_fixture 2.500: 20-80 % time 305ps typ, 376ps min, 224ps max; typ from 2.5 V to 1.1 V
|   falling waveform, R_fixture 50.000, V_fixture 0.0: 20-80 % time 160ps typ, 243ps min, 104ps max; typ from 1.29 V to 0 V
[Pulldown]
|Voltage   I(typ)   I(min)   I(max)
-2.5V     -2.991A    -2.35A     -4.092A
-1.132V   -475mA     -476.9mA   -485.2mA
-1.056V   -351.6mA   -382.8mA   -321.7mA
-980mV    -239mA     -292.8mA   -190.2mA
-904mV    -145.4mA   -209.4mA   -121mA
-828mV    -82.6mA    -136.3mA   -101mA
-676mV    -44.46mA   -39.99mA   -67.9mA
-524mV    -25.56mA   -16.43mA   -38.82mA
236mV     9.262mA    5.959mA    14.32mA
844mV     24.96mA    16.05mA    38.3mA
3.2V      37.3mA     27.87mA    50.89mA
5V        115.7mA    83.75mA    173.5mA
[Pullup]
|Voltage   I(typ)   I(min)   I(max)
-2.5V     144mA      105mA      234.2mA
-548mV    22.4mA     17.12mA    35.05mA
136mV     -4.58mA    -3.289mA   -7.395mA
2.948V    -30.82mA   -24.51mA   -51.85mA
3.1V      -40.88mA   -65.28mA   -55.33mA
3.328V    -86.97mA   -272.6mA   -88.95mA
3.404V    -155.7mA   -361.4mA   -104.1mA
3.556V    -375mA     -551.2mA   -145.3mA
3.632V    -500.8mA   -649.9mA   -245.9mA
3.708V    -631.5mA   -750.2mA   -403.3mA
3.784V    -765.1mA   -851.7mA   -581.6mA
5V        -3.022A    -2.541A    -3.796A
[Ramp]
| variable   typ   min   max
dV/dt_r   0.771/0.329n   0.552/0.395n   1.068/0.192n
dV/dt_f   0.839/0.307n   0.578/0.365n   1.111/0.224n
R_load = 50.000
[Rising Waveform]
R_fixture= 50.000
V_fixture= 0.0
V_fixture_min= 0.0
V_fixture_max= 0.0
|time   V(typ)   V(min)   V(max)
0s        6.01nV     44.68nV    20.69nV
596ps     41.61uV    -3.104uV   -23.3mV
798ps     -160.4uV   -3.104uV   1.262V
1.039ns   -29.88mV   21.17uV    1.64V
1.28ns    749.3mV    29.95uV    1.716V
1.471ns   1.033V     -7.047mV   1.74V
1.732ns   1.169V     -11.99mV   1.761V
2.208ns   1.243V     715.9mV    1.776V
2.929ns   1.271V     877.6mV    1.779V
20ns      1.286V     919.6mV    1.779V
[Rising Waveform]
R_fixture= 50.000
V_fixture= 2.500
V_fixture_min= 2.380
V_fixture_max= 2.630
|time   V(typ)   V(min)   V(max)
0s        1.102V     1.416V     778.2mV
540ps     1.102V     1.416V     792.5mV
588ps     1.102V     1.416V     1.033V
711ps     1.103V     1.416V     2.261V
911ps     1.113V     1.416V     2.556V
1.234ns   2.331V     1.418V     2.606V
1.488ns   2.453V     1.443V     2.619V
1.889ns   2.483V     2.235V     2.627V
2.317ns   2.494V     2.356V     2.629V
20ns      2.5V       2.38V      2.63V
[Falling Waveform]
R_fixture= 50.000
V_fixture= 2.500
V_fixture_min= 2.380
V_fixture_max= 2.630
|time   V(typ)   V(min)   V(max)
0s        2.5V       2.38V      2.63V
611ps     2.5V       2.38V      2.671V
822ps     2.5V       2.38V      1.368V
1.089ns   2.542V     2.38V      916mV
1.333ns   1.655V     2.38V      833.6mV
1.48ns    1.393V     2.38V      814.2mV
1.87ns    1.181V     2.416V     790.9mV
2.436ns   1.122V     1.57V      780.9mV
3.308ns   1.105V     1.438V     778.4mV
20ns      1.102V     1.416V     778.1mV
[Falling Waveform]
R_fixture= 50.000
V_fixture= 0.0
V_fixture_min= 0.0
V_fixture_max= 0.0
|time   V(typ)   V(min)   V(max)
0s        1.286V     919.6mV    1.779V
577ps     1.286V     919.6mV    1.761V
758ps     1.285V     919.7mV    244.6mV
1.004ns   1.265V     919.7mV    42.09mV
1.128ns   763.1mV    919.7mV    25.66mV
1.364ns   87.08mV    919.6mV    10.99mV
1.706ns   20.53mV    894mV      3.701mV
2.066ns   9.295mV    145.5mV    1.139mV
2.501ns   3.83mV     18.09mV    304.8uV
20ns      -153.2nV   -114.2nV   -165.9nV
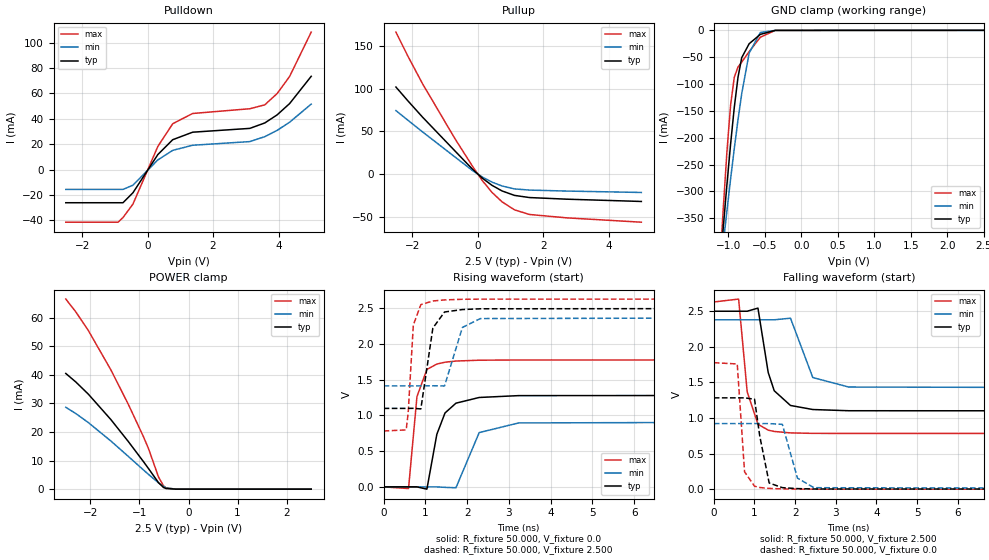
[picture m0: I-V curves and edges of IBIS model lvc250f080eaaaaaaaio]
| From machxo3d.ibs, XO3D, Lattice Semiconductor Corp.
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|   Model lvc250f080eaaaaaaaio
[Model] lvc250f080eaaaaaaaio
Model_type I/O
Polarity   Non-Inverting
Enable   Active-Low
Vinl =  0.700V
Vinh =  1.700V
Vmeas =  1.250V
Cref =  0.0F
Rref =  1.000M
Vref =  0.0V
C_comp   4.200pF   3.800pF   7.500pF
[Temperature Range]   25.000   0.105k   -40.000
[Voltage Range]   2.500V   2.380V   2.630V
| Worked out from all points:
|   slope of the pulldown table from 0 to 0.375 V, typ, clamps not added: 27.2 ohm
|   slope of the pullup table from 0 to 0.375 V, typ, clamps not added: 32.5 ohm
|   GND clamp passes 1 mA (typ) near -0.43 V on its own axis
|   POWER clamp passes 1 mA (typ) near -0.54 V on its own axis
|   rising waveform, R_fixture 50.000, V_fixture 0.0: 20-80 % time 324ps typ, 400ps min, 194ps max; typ from 0 V to 1.28 V
|   rising waveform, R_fixture 50.000, V_fixture 2.500: 20-80 % time 185ps typ, 278ps min, 111ps max; typ from 1.1 V to 2.5 V
|   falling waveform, R_fixture 50.000, V_fixture 2.500: 20-80 % time 303ps typ, 375ps min, 220ps max; typ from 2.5 V to 1.1 V
|   falling waveform, R_fixture 50.000, V_fixture 0.0: 20-80 % time 158ps typ, 244ps min, 103ps max; typ from 1.28 V to 0 V
[Pulldown]
|Voltage   I(typ)   I(min)   I(max)
-2.5V     -26.15mA   -15.63mA   -41.49mA
-904mV    -26.15mA   -15.63mA   -41.49mA
-752mV    -26.15mA   -15.63mA   -37.84mA
-448mV    -18.28mA   -12.33mA   -27.2mA
312mV     11.8mA     7.606mA    18.2mA
768mV     23.56mA    15.16mA    36.16mA
1.376V    29.47mA    19.17mA    44.23mA
3.124V    32.48mA    22.07mA    47.96mA
3.58V     36.75mA    25.93mA    51.02mA
3.96V     43.16mA    30.94mA    59.98mA
4.34V     52.05mA    37.36mA    73.45mA
5V        73.54mA    51.63mA    108.4mA
[Pullup]
|Voltage   I(typ)   I(min)   I(max)
-2.5V     101.8mA    74.28mA    166mA
-2.144V   86.08mA    63.33mA    138.6mA
-1.688V   66.67mA    49.43mA    105.7mA
-700mV    27.27mA    20.17mA    41.68mA
-168mV    6.114mA    4.46mA     9.719mA
136mV     -4.568mA   -3.281mA   -7.374mA
440mV     -13.18mA   -9.386mA   -21.47mA
744mV     -19.64mA   -13.85mA   -32.38mA
1.124V    -24.85mA   -17.24mA   -41.72mA
1.58V     -27.35mA   -18.62mA   -47.12mA
2.72V     -29.25mA   -19.77mA   -51.08mA
5V        -31.92mA   -21.41mA   -56.14mA
[GND_clamp]
|Voltage   I(typ)   I(min)   I(max)
-2.5V     -2.99A     -2.35A     -4.091A
-1.123V   -455.1mA   -463.2mA   -453.6mA
-1.072V   -370.5mA   -399.5mA   -336.3mA
-1.021V   -289.1mA   -337.4mA   -228.5mA
-970mV    -212.6mA   -277.3mA   -139.9mA
-919mV    -143.6mA   -220.1mA   -87.34mA
-868mV    -87.35mA   -166.5mA   -68.39mA
-817mV    -50.9mA    -117.8mA   -59.07mA
-715mV    -24.94mA   -42.34mA   -39.63mA
-562mV    -7.547mA   -4.077mA   -12.85mA
-358mV    -114uA     -53.77uA   -172.8uA
2.5V      0A         0A         0A
[POWER_clamp]
|Voltage   I(typ)   I(min)   I(max)
-2.5V     40.49mA    28.66mA    66.53mA
-2.294V   37.48mA    26.44mA    61.99mA
-2.039V   33.22mA    23.28mA    55.47mA
-1.58V    24.32mA    16.83mA    41.7mA
-1.223V   16.6mA     11.41mA    29.58mA
-917mV    9.616mA    6.712mA    18.32mA
-815mV    7.205mA    5.171mA    14.19mA
-611mV    2.275mA    2.213mA    4.254mA
-509mV    589.4uA    929.1uA    1.152mA
-458mV    232.9uA    445.2uA    427.7uA
-254mV    3.785uA    4.472uA    4.114uA
2.5V      0A         0A         3.667nA
[Ramp]
| variable   typ   min   max
dV/dt_r   0.770/0.324n   0.553/0.395n   1.066/0.189n
dV/dt_f   0.841/0.306n   0.579/0.364n   1.108/0.220n
R_load = 50.000
[Rising Waveform]
R_fixture= 50.000
V_fixture= 0.0
V_fixture_min= 0.0
V_fixture_max= 0.0
|time   V(typ)   V(min)   V(max)
0s        6.216nV    45.16nV    21.49nV
596ps     44.53uV    -123.3nV   -23.36mV
798ps     -158.4uV   -123.3nV   1.265V
1.036ns   -31.92mV   24.65uV    1.644V
1.274ns   735.9mV    19.41uV    1.72V
1.47ns    1.035V     -6.722mV   1.746V
1.732ns   1.172V     -12.04mV   1.762V
2.289ns   1.252V     760.1mV    1.774V
3.234ns   1.278V     895.6mV    1.777V
20ns      1.283V     921.3mV    1.777V
[Rising Waveform]
R_fixture= 50.000
V_fixture= 2.500
V_fixture_min= 2.380
V_fixture_max= 2.630
|time   V(typ)   V(min)   V(max)
0s        1.099V     1.414V     783mV
540ps     1.099V     1.414V     797.6mV
588ps     1.099V     1.414V     1.04V
711ps     1.1V       1.414V     2.266V
891ps     1.092V     1.414V     2.552V
1.179ns   2.224V     1.416V     2.603V
1.459ns   2.449V     1.413V     2.618V
1.887ns   2.483V     2.233V     2.627V
2.317ns   2.494V     2.357V     2.629V
20ns      2.5V       2.38V      2.63V
[Falling Waveform]
R_fixture= 50.000
V_fixture= 2.500
V_fixture_min= 2.380
V_fixture_max= 2.630
|time   V(typ)   V(min)   V(max)
0s        2.5V       2.38V      2.63V
611ps     2.5V       2.38V      2.671V
822ps     2.5V       2.38V      1.365V
1.086ns   2.544V     2.38V      913.3mV
1.338ns   1.64V      2.38V      829mV
1.486ns   1.383V     2.38V      810.8mV
1.886ns   1.176V     2.402V     790.6mV
2.435ns   1.119V     1.568V     784mV
3.319ns   1.102V     1.435V     783.1mV
20ns      1.099V     1.414V     782.9mV
[Falling Waveform]
R_fixture= 50.000
V_fixture= 0.0
V_fixture_min= 0.0
V_fixture_max= 0.0
|time   V(typ)   V(min)   V(max)
0s        1.283V     921.3mV    1.777V
577ps     1.283V     921.2mV    1.759V
757ps     1.283V     921.3mV    244.5mV
1.002ns   1.264V     921.3mV    40.9mV
1.132ns   741.5mV    921.3mV    23.61mV
1.362ns   86.49mV    921.3mV    10.57mV
1.686ns   21.25mV    910.8mV    3.315mV
2.057ns   7.846mV    155.8mV    903.3uV
2.463ns   2.617mV    20.68mV    292.7uV
20ns      67.74nV    -41.98nV   -218.8nV
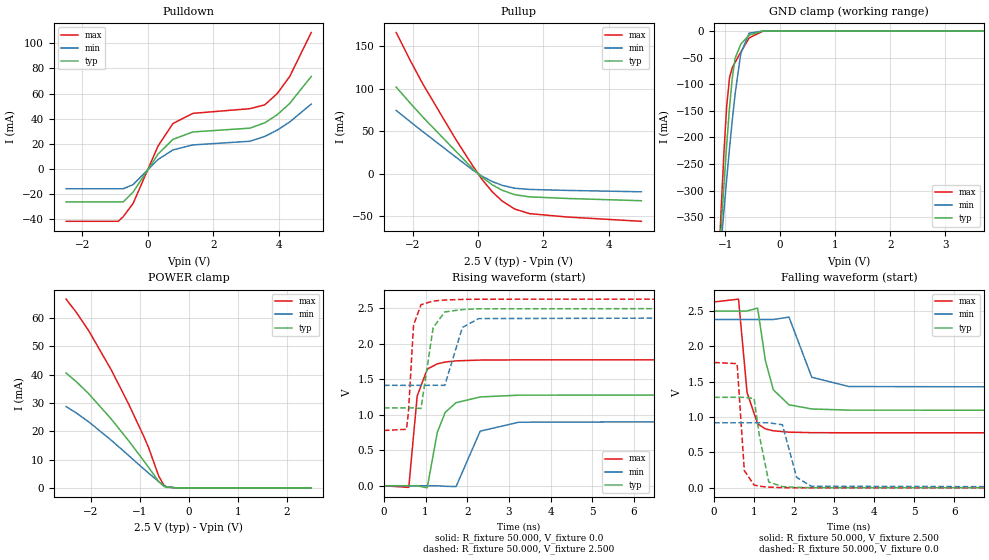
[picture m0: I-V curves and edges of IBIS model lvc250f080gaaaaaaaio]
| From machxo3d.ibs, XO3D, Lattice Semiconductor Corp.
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|   Model lvc250f080gaaaaaaaio
[Model] lvc250f080gaaaaaaaio
Model_type I/O
Polarity   Non-Inverting
Enable   Active-Low
Vinl =  0.700V
Vinh =  1.700V
Vmeas =  1.250V
Cref =  0.0F
Rref =  1.000M
Vref =  0.0V
C_comp   4.200pF   3.800pF   7.500pF
[Temperature Range]   25.000   0.105k   -40.000
[Voltage Range]   2.500V   2.380V   2.630V
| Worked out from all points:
|   slope of the pulldown table from 0 to 0.375 V, typ, clamps not added: 27.2 ohm
|   slope of the pullup table from 0 to 0.375 V, typ, clamps not added: 32.5 ohm
|   GND clamp passes 1 mA (typ) near -0.43 V on its own axis
|   POWER clamp passes 1 mA (typ) near -0.54 V on its own axis
|   rising waveform, R_fixture 50.000, V_fixture 0.0: 20-80 % time 325ps typ, 401ps min, 192ps max; typ from 0 V to 1.28 V
|   rising waveform, R_fixture 50.000, V_fixture 2.500: 20-80 % time 185ps typ, 278ps min, 110ps max; typ from 1.1 V to 2.5 V
|   falling waveform, R_fixture 50.000, V_fixture 2.500: 20-80 % time 304ps typ, 376ps min, 220ps max; typ from 2.5 V to 1.09 V
|   falling waveform, R_fixture 50.000, V_fixture 0.0: 20-80 % time 157ps typ, 242ps min, 103ps max; typ from 1.28 V to 0 V
[Pulldown]
|Voltage   I(typ)   I(min)   I(max)
-2.5V     -26.15mA   -15.63mA   -41.49mA
-904mV    -26.15mA   -15.63mA   -41.49mA
-752mV    -26.15mA   -15.63mA   -37.84mA
-448mV    -18.28mA   -12.33mA   -27.2mA
312mV     11.8mA     7.606mA    18.2mA
768mV     23.56mA    15.16mA    36.16mA
1.376V    29.47mA    19.17mA    44.23mA
3.124V    32.48mA    22.07mA    47.96mA
3.58V     36.74mA    25.93mA    51.02mA
3.96V     43.16mA    30.94mA    59.98mA
4.34V     52.05mA    37.36mA    73.45mA
5V        73.54mA    51.63mA    108.4mA
[Pullup]
|Voltage   I(typ)   I(min)   I(max)
-2.5V     101.8mA    74.28mA    166mA
-2.068V   82.79mA    61mA       133mA
-1.688V   66.67mA    49.43mA    105.7mA
-700mV    27.27mA    20.17mA    41.68mA
-168mV    6.114mA    4.46mA     9.719mA
136mV     -4.568mA   -3.281mA   -7.374mA
440mV     -13.18mA   -9.386mA   -21.47mA
744mV     -19.64mA   -13.85mA   -32.38mA
1.124V    -24.85mA   -17.24mA   -41.72mA
1.58V     -27.35mA   -18.62mA   -47.12mA
2.72V     -29.25mA   -19.77mA   -51.08mA
5V        -31.92mA   -21.41mA   -56.14mA
[GND_clamp]
|Voltage   I(typ)   I(min)   I(max)
-2.5V     -2.99A     -2.35A     -4.091A
-1.123V   -455.1mA   -463.2mA   -453.7mA
-1.072V   -370.5mA   -399.5mA   -336.3mA
-1.021V   -289.2mA   -337.4mA   -228.6mA
-970mV    -212.6mA   -277.4mA   -140mA
-919mV    -143.6mA   -220.1mA   -87.4mA
-868mV    -87.39mA   -166.5mA   -68.45mA
-817mV    -50.94mA   -117.8mA   -59.13mA
-715mV    -24.99mA   -42.37mA   -39.7mA
-562mV    -7.608mA   -4.125mA   -12.95mA
-307mV    -97.66uA   -51.76uA   -173.8uA
5V        114uA      49.35uA    266.8uA
[POWER_clamp]
|Voltage   I(typ)   I(min)   I(max)
-2.5V     40.55mA    28.7mA     66.64mA
-2.294V   37.53mA    26.47mA    62.05mA
-2.039V   33.25mA    23.31mA    55.5mA
-1.58V    24.33mA    16.84mA    41.69mA
-1.223V   16.6mA     11.41mA    29.54mA
-917mV    9.596mA    6.709mA    18.24mA
-815mV    7.18mA     5.166mA    14.11mA
-611mV    2.243mA    2.205mA    4.167mA
-509mV    558uA      921.7uA    1.059mA
-458mV    208uA      438.7uA    350.8uA
-254mV    2.162uA    3.635uA    1.029uA
2.5V      0A         0A         0A
[Ramp]
| variable   typ   min   max
dV/dt_r   0.768/0.324n   0.552/0.395n   1.063/0.189n
dV/dt_f   0.842/0.305n   0.580/0.364n   1.109/0.219n
R_load = 50.000
[Rising Waveform]
R_fixture= 50.000
V_fixture= 0.0
V_fixture_min= 0.0
V_fixture_max= 0.0
|time   V(typ)   V(min)   V(max)
0s        6.01nV     44.68nV    20.69nV
596ps     44.49uV    -155.9nV   -23.3mV
798ps     -161.8uV   -155.9nV   1.262V
1.039ns   -29.88mV   24.63uV    1.641V
1.28ns    749.3mV    17.57uV    1.716V
1.471ns   1.033V     -7.906mV   1.741V
1.732ns   1.169V     -11.99mV   1.758V
2.311ns   1.25V      768.3mV    1.769V
3.238ns   1.275V     894.2mV    1.772V
20ns      1.279V     919.6mV    1.772V
[Rising Waveform]
R_fixture= 50.000
V_fixture= 2.500
V_fixture_min= 2.380
V_fixture_max= 2.630
|time   V(typ)   V(min)   V(max)
0s        1.096V     1.413V     778.2mV
541ps     1.096V     1.413V     794.5mV
588ps     1.096V     1.413V     1.033V
711ps     1.096V     1.413V     2.261V
890ps     1.087V     1.413V     2.549V
1.181ns   2.226V     1.414V     2.6V
1.461ns   2.447V     1.413V     2.615V
1.883ns   2.48V      2.228V     2.623V
2.273ns   2.491V     2.353V     2.626V
20ns      2.498V     2.379V     2.627V
[Falling Waveform]
R_fixture= 50.000
V_fixture= 2.500
V_fixture_min= 2.380
V_fixture_max= 2.630
|time   V(typ)   V(min)   V(max)
0s        2.498V     2.379V     2.627V
611ps     2.498V     2.379V     2.667V
824ps     2.499V     2.379V     1.349V
1.088ns   2.54V      2.379V     905.1mV
1.283ns   1.798V     2.379V     833.6mV
1.48ns    1.386V     2.379V     806.3mV
1.872ns   1.174V     2.413V     787.2mV
2.442ns   1.115V     1.563V     780.1mV
3.37ns    1.098V     1.432V     778.2mV
20ns      1.095V     1.413V     778.2mV
[Falling Waveform]
R_fixture= 50.000
V_fixture= 0.0
V_fixture_min= 0.0
V_fixture_max= 0.0
|time   V(typ)   V(min)   V(max)
0s        1.279V     919.6mV    1.772V
576ps     1.28V      919.5mV    1.755V
756ps     1.279V     919.7mV    243.3mV
1ns       1.263V     919.7mV    40.13mV
1.132ns   737.5mV    919.7mV    22.9mV
1.368ns   81.82mV    919.6mV    10.11mV
1.708ns   18.28mV    892.1mV    3.089mV
2.063ns   7.03mV     148.5mV    1.009mV
2.43ns    2.771mV    22.71mV    351uV
20ns      -130.7nV   -85.29nV   -377.9nV
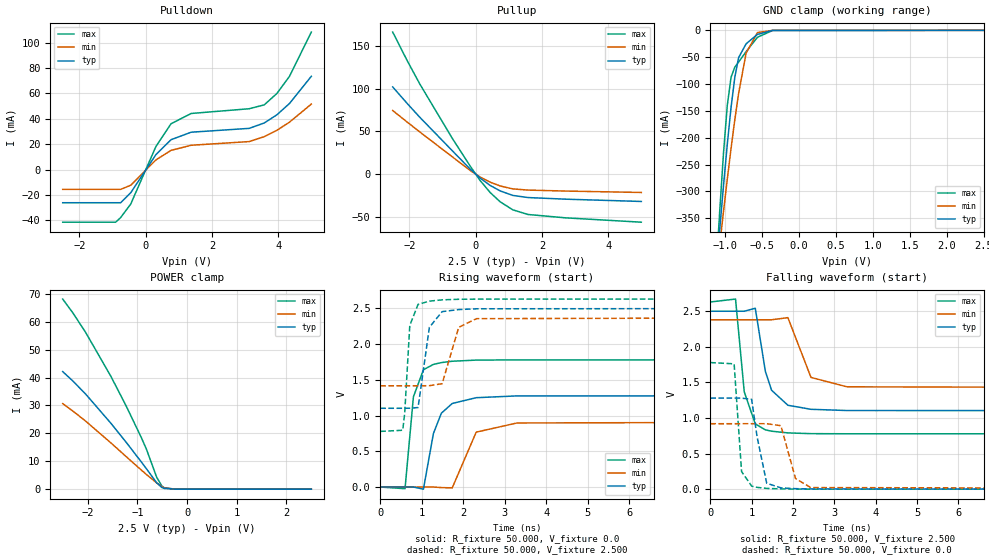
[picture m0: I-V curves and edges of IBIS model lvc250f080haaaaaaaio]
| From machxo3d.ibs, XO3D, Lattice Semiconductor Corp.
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|   Model lvc250f080haaaaaaaio
[Model] lvc250f080haaaaaaaio
Model_type I/O
Polarity   Non-Inverting
Enable   Active-Low
Vinl =  0.700V
Vinh =  1.700V
Vmeas =  1.250V
Cref =  0.0F
Rref =  1.000M
Vref =  0.0V
C_comp   4.200pF   3.800pF   7.500pF
[Temperature Range]   25.000   0.105k   -40.000
[Voltage Range]   2.500V   2.380V   2.630V
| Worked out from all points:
|   slope of the pulldown table from 0 to 0.375 V, typ, clamps not added: 27.2 ohm
|   slope of the pullup table from 0 to 0.375 V, typ, clamps not added: 32.5 ohm
|   GND clamp passes 1 mA (typ) near -0.43 V on its own axis
|   POWER clamp passes 1 mA (typ) near -0.54 V on its own axis
|   rising waveform, R_fixture 50.000, V_fixture 0.0: 20-80 % time 325ps typ, 401ps min, 195ps max; typ from 0 V to 1.28 V
|   rising waveform, R_fixture 50.000, V_fixture 2.500: 20-80 % time 185ps typ, 279ps min, 111ps max; typ from 1.1 V to 2.5 V
|   falling waveform, R_fixture 50.000, V_fixture 2.500: 20-80 % time 305ps typ, 376ps min, 224ps max; typ from 2.5 V to 1.1 V
|   falling waveform, R_fixture 50.000, V_fixture 0.0: 20-80 % time 158ps typ, 245ps min, 104ps max; typ from 1.28 V to 0 V
[Pulldown]
|Voltage   I(typ)   I(min)   I(max)
-2.5V     -26.15mA   -15.63mA   -41.49mA
-904mV    -26.15mA   -15.63mA   -41.49mA
-752mV    -26.15mA   -15.63mA   -37.84mA
-448mV    -18.28mA   -12.33mA   -27.2mA
312mV     11.8mA     7.606mA    18.2mA
768mV     23.56mA    15.16mA    36.16mA
1.376V    29.47mA    19.17mA    44.23mA
3.124V    32.48mA    22.07mA    47.96mA
3.58V     36.74mA    25.93mA    51.02mA
3.96V     43.16mA    30.94mA    59.98mA
4.34V     52.05mA    37.36mA    73.44mA
5V        73.53mA    51.63mA    108.4mA
[Pullup]
|Voltage   I(typ)   I(min)   I(max)
-2.5V     101.9mA    74.32mA    166mA
-2.068V   82.81mA    61.02mA    133mA
-1.688V   66.68mA    49.44mA    105.7mA
-700mV    27.27mA    20.17mA    41.68mA
-168mV    6.114mA    4.46mA     9.719mA
136mV     -4.568mA   -3.281mA   -7.374mA
440mV     -13.18mA   -9.386mA   -21.47mA
744mV     -19.64mA   -13.85mA   -32.38mA
1.124V    -24.85mA   -17.24mA   -41.72mA
1.58V     -27.35mA   -18.62mA   -47.12mA
2.72V     -29.25mA   -19.77mA   -51.08mA
5V        -31.92mA   -21.41mA   -56.14mA
[GND_clamp]
|Voltage   I(typ)   I(min)   I(max)
-2.5V     -2.99A     -2.35A     -4.091A
-1.123V   -455.1mA   -463.2mA   -453.7mA
-1.072V   -370.5mA   -399.5mA   -336.3mA
-1.021V   -289.2mA   -337.4mA   -228.6mA
-970mV    -212.6mA   -277.4mA   -140mA
-919mV    -143.6mA   -220.1mA   -87.4mA
-868mV    -87.39mA   -166.5mA   -68.45mA
-817mV    -50.94mA   -117.8mA   -59.13mA
-715mV    -24.99mA   -42.37mA   -39.7mA
-562mV    -7.608mA   -4.125mA   -12.95mA
-358mV    -194.9uA   -98.36uA   -303.6uA
2.5V      13.17nA    0A         -19.29uA
[POWER_clamp]
|Voltage   I(typ)   I(min)   I(max)
-2.5V     42.14mA    30.66mA    68.15mA
-2.294V   38.75mA    27.99mA    63.15mA
-2.039V   34.09mA    24.4mA     56.2mA
-1.529V   23.59mA    16.56mA    40.38mA
-1.223V   16.79mA    11.66mA    29.8mA
-917mV    9.72mA     6.817mA    18.42mA
-815mV    7.285mA    5.246mA    14.27mA
-611mV    2.32mA     2.253mA    4.314mA
-509mV    627.1uA    959.6uA    1.202mA
-458mV    269.3uA    472.4uA    476.3uA
-254mV    28.45uA    20.72uA    43.74uA
2.5V      0A         0A         0A
[Ramp]
| variable   typ   min   max
dV/dt_r   0.768/0.324n   0.552/0.395n   1.068/0.192n
dV/dt_f   0.839/0.307n   0.578/0.365n   1.111/0.224n
R_load = 50.000
[Rising Waveform]
R_fixture= 50.000
V_fixture= 0.0
V_fixture_min= 0.0
V_fixture_max= 0.0
|time   V(typ)   V(min)   V(max)
0s        6.01nV     44.68nV    20.69nV
596ps     44.48uV    -179.9nV   -23.3mV
798ps     -161.8uV   -179.9nV   1.262V
1.039ns   -29.88mV   24.63uV    1.641V
1.28ns    749.3mV    17.57uV    1.716V
1.471ns   1.033V     -7.906mV   1.741V
1.732ns   1.169V     -11.99mV   1.76V
2.311ns   1.25V      768.3mV    1.776V
3.293ns   1.275V     896.3mV    1.779V
20ns      1.279V     919.6mV    1.779V
[Rising Waveform]
R_fixture= 50.000
V_fixture= 2.500
V_fixture_min= 2.380
V_fixture_max= 2.630
|time   V(typ)   V(min)   V(max)
0s        1.102V     1.416V     778.2mV
541ps     1.102V     1.416V     794.5mV
588ps     1.102V     1.416V     1.033V
711ps     1.103V     1.416V     2.261V
910ps     1.112V     1.416V     2.556V
1.183ns   2.235V     1.418V     2.601V
1.49ns    2.454V     1.446V     2.619V
1.889ns   2.483V     2.235V     2.627V
2.319ns   2.494V     2.356V     2.629V
20ns      2.5V       2.38V      2.63V
[Falling Waveform]
R_fixture= 50.000
V_fixture= 2.500
V_fixture_min= 2.380
V_fixture_max= 2.630
|time   V(typ)   V(min)   V(max)
0s        2.5V       2.38V      2.63V
611ps     2.5V       2.38V      2.671V
822ps     2.5V       2.38V      1.368V
1.089ns   2.542V     2.38V      916.1mV
1.333ns   1.655V     2.38V      833.6mV
1.483ns   1.39V      2.38V      814.5mV
1.878ns   1.179V     2.41V      790.4mV
2.436ns   1.122V     1.57V      780mV
3.308ns   1.105V     1.438V     778.3mV
20ns      1.102V     1.416V     778.2mV
[Falling Waveform]
R_fixture= 50.000
V_fixture= 0.0
V_fixture_min= 0.0
V_fixture_max= 0.0
|time   V(typ)   V(min)   V(max)
0s        1.279V     919.6mV    1.779V
577ps     1.28V      919.5mV    1.761V
757ps     1.279V     919.7mV    247.8mV
1.001ns   1.262V     919.7mV    43.03mV
1.132ns   737.5mV    919.7mV    25.35mV
1.365ns   83.54mV    919.6mV    10.82mV
1.708ns   18.28mV    892.1mV    3.593mV
2.063ns   7.03mV     148.5mV    1.074mV
2.43ns    2.771mV    22.71mV    378.7uV
20ns      -130.7nV   -85.29nV   -292.6nV
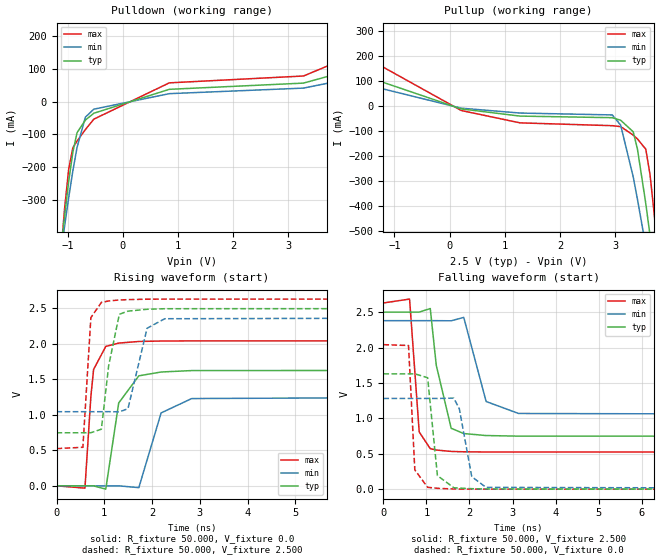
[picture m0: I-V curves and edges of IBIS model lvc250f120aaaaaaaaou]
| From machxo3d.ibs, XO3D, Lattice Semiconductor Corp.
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|   Model lvc250f120aaaaaaaaou
[Model] lvc250f120aaaaaaaaou
Model_type Output
Polarity   Non-Inverting
Enable   Active-High
Vmeas =  1.250V
Cref =  0.0F
Rref =  1.000M
Vref =  0.0V
C_comp   4.200pF   3.800pF   7.500pF
[Temperature Range]   25.000   0.105k   -40.000
[Voltage Range]   2.500V   2.380V   2.630V
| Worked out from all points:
|   slope of the pulldown table from 0 to 0.375 V, typ, clamps not added: 18.1 ohm
|   slope of the pullup table from 0 to 0.375 V, typ, clamps not added: 21.7 ohm
|   rising waveform, R_fixture 50.000, V_fixture 0.0: 20-80 % time 235ps typ, 346ps min, 127ps max; typ from 0 V to 1.63 V
|   rising waveform, R_fixture 50.000, V_fixture 2.500: 20-80 % time 161ps typ, 260ps min, 87.7ps max; typ from 0.747 V to 2.5 V
|   falling waveform, R_fixture 50.000, V_fixture 2.500: 20-80 % time 219ps typ, 328ps min, 136ps max; typ from 2.5 V to 0.747 V
|   falling waveform, R_fixture 50.000, V_fixture 0.0: 20-80 % time 131ps typ, 212ps min, 81.1ps max; typ from 1.63 V to 0 V
[Pulldown]
|Voltage   I(typ)   I(min)   I(max)
-2.5V     -2.991A    -2.351A    -4.092A
-1.132V   -477.3mA   -478.1mA   -490.1mA
-1.056V   -355mA     -384.2mA   -331.8mA
-980mV    -244.9mA   -294.8mA   -207.7mA
-904mV    -155.3mA   -212.2mA   -141.7mA
-828mV    -95.41mA   -140.5mA   -120.9mA
-676mV    -56.77mA   -47.71mA   -85.72mA
-524mV    -35.9mA    -23.48mA   -54.06mA
844mV     37.3mA     24.02mA    57.11mA
3.276V    56.34mA    41.03mA    78.1mA
4.188V    98.83mA    72.08mA    142.2mA
5V        150.8mA    107.2mA    226.3mA
[Pullup]
|Voltage   I(typ)   I(min)   I(max)
-2.5V     193.6mA    140.2mA    316.2mA
212mV     -10.39mA   -7.447mA   -16.81mA
1.276V    -39.13mA   -26.93mA   -66.27mA
2.948V    -45.51mA   -34.45mA   -77.55mA
3.1V      -55.71mA   -75.32mA   -81.24mA
3.328V    -102mA     -282.7mA   -115.2mA
3.404V    -170.7mA   -371.5mA   -130.5mA
3.556V    -390.2mA   -561.5mA   -171.8mA
3.632V    -516.1mA   -660.2mA   -272.5mA
3.708V    -646.7mA   -760.5mA   -430mA
3.784V    -780.5mA   -862mA     -608.4mA
5V        -3.038A    -2.551A    -3.824A
[Ramp]
| variable   typ   min   max
dV/dt_r   0.978/0.234n   0.769/0.347n   1.225/0.127n
dV/dt_f   1.052/0.218n   0.801/0.327n   1.263/0.135n
R_load = 50.000
[Rising Waveform]
R_fixture= 50.000
V_fixture= 0.0
V_fixture_min= 0.0
V_fixture_max= 0.0
|time   V(typ)   V(min)   V(max)
0s        4.635nV    35nV       15.53nV
595ps     40.53uV    -5.812uV   -32.32mV
720ps     124.8uV    -5.812uV   1.265V
776ps     -12.71uV   -5.812uV   1.639V
1.031ns   -46.95mV   19.02uV    1.963V
1.302ns   1.167V     -204.3uV   2.01V
1.723ns   1.549V     -25.4mV    2.033V
2.19ns    1.603V     1.027V     2.039V
2.83ns    1.623V     1.229V     2.041V
20ns      1.629V     1.281V     2.041V
[Rising Waveform]
R_fixture= 50.000
V_fixture= 2.500
V_fixture_min= 2.380
V_fixture_max= 2.630
|time   V(typ)   V(min)   V(max)
0s        747.2mV    1.044V     524.3mV
552ps     747.2mV    1.044V     542.8mV
719ps     747.9mV    1.044V     2.368V
939ps     797.4mV    1.044V     2.583V
1.091ns   1.689V     1.045V     2.603V
1.315ns   2.416V     1.041V     2.617V
1.496ns   2.46V      1.087V     2.622V
1.896ns   2.486V     2.219V     2.628V
2.265ns   2.494V     2.353V     2.629V
20ns      2.5V       2.38V      2.63V
[Falling Waveform]
R_fixture= 50.000
V_fixture= 2.500
V_fixture_min= 2.380
V_fixture_max= 2.630
|time   V(typ)   V(min)   V(max)
0s        2.5V       2.38V      2.63V
608ps     2.5V       2.38V      2.685V
832ps     2.501V     2.38V      807.8mV
1.089ns   2.551V     2.38V      572.2mV
1.228ns   1.751V     2.38V      552.5mV
1.575ns   860mV      2.378V     533mV
1.867ns   785.6mV    2.426V     527.9mV
2.387ns   757.3mV    1.238V     524.9mV
3.141ns   749mV      1.069V     524.4mV
20ns      747.2mV    1.044V     524.3mV
[Falling Waveform]
R_fixture= 50.000
V_fixture= 0.0
V_fixture_min= 0.0
V_fixture_max= 0.0
|time   V(typ)   V(min)   V(max)
0s        1.629V     1.281V     2.041V
584ps     1.629V     1.281V     2.029V
730ps     1.629V     1.281V     272mV
1.028ns   1.574V     1.281V     26.16mV
1.255ns   191.9mV    1.281V     11.85mV
1.636ns   19.97mV    1.286V     2.823mV
1.764ns   15.32mV    1.136V     1.835mV
2.053ns   6.665mV    176.2mV    679.1uV
2.386ns   2.837mV    25.17mV    269.2uV
20ns      -13.2nV    121.9nV    -376.3nV
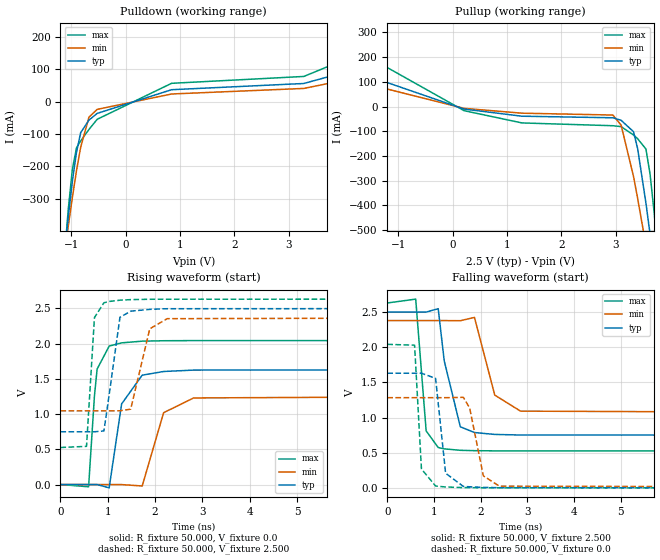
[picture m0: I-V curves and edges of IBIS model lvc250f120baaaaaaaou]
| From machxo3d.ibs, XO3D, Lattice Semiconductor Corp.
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|   Model lvc250f120baaaaaaaou
[Model] lvc250f120baaaaaaaou
Model_type Output
Polarity   Non-Inverting
Enable   Active-High
Vmeas =  1.250V
Cref =  0.0F
Rref =  1.000M
Vref =  0.0V
C_comp   4.200pF   3.800pF   7.500pF
[Temperature Range]   25.000   0.105k   -40.000
[Voltage Range]   2.500V   2.380V   2.630V
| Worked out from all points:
|   slope of the pulldown table from 0 to 0.375 V, typ, clamps not added: 18.1 ohm
|   slope of the pullup table from 0 to 0.375 V, typ, clamps not added: 21.7 ohm
|   rising waveform, R_fixture 50.000, V_fixture 0.0: 20-80 % time 234ps typ, 347ps min, 127ps max; typ from 0.001 V to 1.63 V
|   rising waveform, R_fixture 50.000, V_fixture 2.500: 20-80 % time 160ps typ, 259ps min, 87.6ps max; typ from 0.749 V to 2.5 V
|   falling waveform, R_fixture 50.000, V_fixture 2.500: 20-80 % time 219ps typ, 328ps min, 136ps max; typ from 2.5 V to 0.749 V
|   falling waveform, R_fixture 50.000, V_fixture 0.0: 20-80 % time 130ps typ, 212ps min, 81.2ps max; typ from 1.63 V to 0.001 V
[Pulldown]
|Voltage   I(typ)   I(min)   I(max)
-2.5V     -2.991A    -2.351A    -4.092A
-1.132V   -477.3mA   -478.1mA   -490.2mA
-1.056V   -355.1mA   -384.2mA   -331.9mA
-980mV    -245mA     -294.8mA   -207.8mA
-904mV    -155.3mA   -212.2mA   -141.8mA
-828mV    -95.44mA   -140.5mA   -121mA
-676mV    -56.81mA   -47.74mA   -85.78mA
-524mV    -35.96mA   -23.52mA   -54.15mA
844mV     37.22mA    23.97mA    56.96mA
3.276V    56.41mA    41.13mA    78.15mA
4.112V    95.01mA    69.77mA    136mA
5V        152.4mA    109.5mA    227.6mA
[Pullup]
|Voltage   I(typ)   I(min)   I(max)
-2.5V     195.3mA    142.3mA    317.9mA
212mV     -10.41mA   -7.459mA   -16.84mA
1.276V    -39.2mA    -26.97mA   -66.41mA
2.948V    -45.58mA   -34.48mA   -77.69mA
3.1V      -55.74mA   -75.33mA   -81.34mA
3.328V    -102mA     -282.8mA   -115.2mA
3.404V    -170.8mA   -371.6mA   -130.5mA
3.556V    -390.2mA   -561.5mA   -171.8mA
3.632V    -516.1mA   -660.2mA   -272.6mA
3.708V    -646.8mA   -760.5mA   -430.1mA
3.784V    -780.5mA   -862mA     -608.4mA
5V        -3.038A    -2.551A    -3.824A
[Ramp]
| variable   typ   min   max
dV/dt_r   0.978/0.233n   0.769/0.346n   1.224/0.127n
dV/dt_f   1.051/0.219n   0.800/0.328n   1.262/0.136n
R_load = 50.000
[Rising Waveform]
R_fixture= 50.000
V_fixture= 0.0
V_fixture_min= 0.0
V_fixture_max= 0.0
|time   V(typ)   V(min)   V(max)
0s        990.6uV    778.5uV    1.315mV
595ps     1.031mV    771.5uV    -30.44mV
719ps     1.098mV    771.5uV    1.26V
775ps     971.4uV    771.5uV    1.638V
1.03ns    -45.81mV   856.6uV    1.964V
1.293ns   1.144V     646.5uV    2.01V
1.728ns   1.552V     -19.18mV   2.034V
2.181ns   1.604V     1.02V      2.04V
2.816ns   1.624V     1.229V     2.042V
20ns      1.631V     1.283V     2.042V
[Rising Waveform]
R_fixture= 50.000
V_fixture= 2.500
V_fixture_min= 2.380
V_fixture_max= 2.630
|time   V(typ)   V(min)   V(max)
0s        748.9mV    1.046V     526.3mV
551ps     748.9mV    1.046V     542.7mV
719ps     749.6mV    1.046V     2.369V
919ps     761mV      1.046V     2.578V
1.032ns   1.284V     1.046V     2.597V
1.258ns   2.373V     1.047V     2.615V
1.485ns   2.459V     1.07V      2.623V
1.888ns   2.485V     2.209V     2.628V
2.257ns   2.494V     2.353V     2.629V
20ns      2.5V       2.38V      2.63V
[Falling Waveform]
R_fixture= 50.000
V_fixture= 2.500
V_fixture_min= 2.380
V_fixture_max= 2.630
|time   V(typ)   V(min)   V(max)
0s        2.5V       2.38V      2.63V
608ps     2.5V       2.38V      2.685V
832ps     2.501V     2.38V      811.2mV
1.09ns    2.549V     2.38V      574.3mV
1.219ns   1.808V     2.38V      555.3mV
1.564ns   869.3mV    2.378V     534.9mV
1.867ns   787.5mV    2.425V     529.8mV
2.302ns   760.8mV    1.32V      526.9mV
2.854ns   752.3mV    1.092V     526.4mV
20ns      748.8mV    1.046V     526.2mV
[Falling Waveform]
R_fixture= 50.000
V_fixture= 0.0
V_fixture_min= 0.0
V_fixture_max= 0.0
|time   V(typ)   V(min)   V(max)
0s        1.631V     1.283V     2.042V
584ps     1.631V     1.283V     2.03V
731ps     1.631V     1.283V     269.7mV
1.034ns   1.558V     1.283V     26.92mV
1.249ns   208.3mV    1.283V     13.46mV
1.629ns   21.44mV    1.288V     4.227mV
1.764ns   16mV       1.138V     3.226mV
2.057ns   7.417mV    171.8mV    2.037mV
2.4ns     3.706mV    24.81mV    1.609mV
20ns      990.4uV    778.4uV    1.314mV
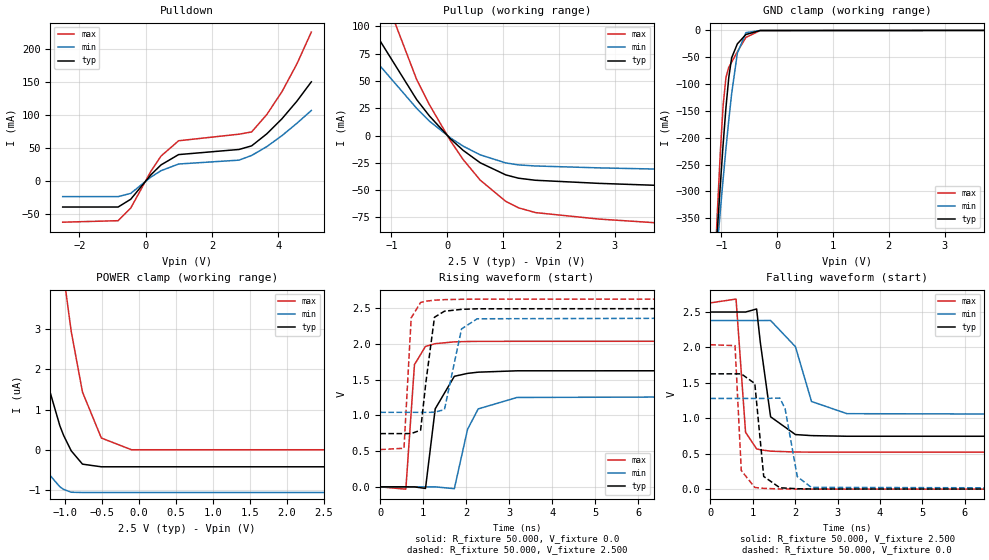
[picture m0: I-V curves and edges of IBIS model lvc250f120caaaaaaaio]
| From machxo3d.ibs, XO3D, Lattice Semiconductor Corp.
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|   Model lvc250f120caaaaaaaio
[Model] lvc250f120caaaaaaaio
Model_type I/O
Polarity   Non-Inverting
Enable   Active-Low
Vinl =  0.700V
Vinh =  1.700V
Vmeas =  1.250V
Cref =  0.0F
Rref =  1.000M
Vref =  0.0V
C_comp   4.200pF   3.800pF   7.500pF
[Temperature Range]   25.000   0.105k   -40.000
[Voltage Range]   2.500V   2.380V   2.630V
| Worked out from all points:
|   slope of the pulldown table from 0 to 0.375 V, typ, clamps not added: 18.1 ohm
|   slope of the pullup table from 0 to 0.375 V, typ, clamps not added: 21.7 ohm
|   GND clamp passes 1 mA (typ) near -0.43 V on its own axis
|   rising waveform, R_fixture 50.000, V_fixture 0.0: 20-80 % time 234ps typ, 349ps min, 127ps max; typ from 0 V to 1.63 V
|   rising waveform, R_fixture 50.000, V_fixture 2.500: 20-80 % time 161ps typ, 259ps min, 87.7ps max; typ from 0.745 V to 2.5 V
|   falling waveform, R_fixture 50.000, V_fixture 2.500: 20-80 % time 217ps typ, 326ps min, 135ps max; typ from 2.5 V to 0.745 V
|   falling waveform, R_fixture 50.000, V_fixture 0.0: 20-80 % time 131ps typ, 211ps min, 80.7ps max; typ from 1.63 V to 0 V
[Pulldown]
|Voltage   I(typ)   I(min)   I(max)
-2.5V     -39.23mA   -23.44mA   -62.24mA
-828mV    -39.23mA   -23.44mA   -59.96mA
-448mV    -27.42mA   -18.49mA   -40.8mA
160mV     9.666mA    6.229mA    14.91mA
464mV     24.66mA    15.88mA    38.02mA
996mV     40.36mA    26.05mA    61.35mA
2.82V     48.17mA    31.96mA    71.35mA
3.2V      53.63mA    39.06mA    74.77mA
3.656V    71.83mA    52.45mA    101.1mA
4.112V    94.62mA    69.08mA    135.6mA
4.568V    121.6mA    87.99mA    178.3mA
5V        150.8mA    107.3mA    226.3mA
[Pullup]
|Voltage   I(typ)   I(min)   I(max)
-2.5V     193.6mA    140.3mA    316.3mA
-1.688V   126.6mA    92.6mA     203.8mA
-548mV    32.97mA    24.94mA    51.35mA
-320mV    17.99mA    13.25mA    28.31mA
60mV      -3.106mA   -2.235mA   -5.004mA
288mV     -13.72mA   -9.814mA   -22.24mA
592mV     -25.01mA   -17.73mA   -40.97mA
1.048V    -36.09mA   -25.12mA   -60.34mA
1.276V    -39.13mA   -26.93mA   -66.27mA
1.58V     -41.03mA   -27.92mA   -70.68mA
2.72V     -43.87mA   -29.66mA   -76.62mA
5V        -47.88mA   -32.11mA   -84.21mA
[GND_clamp]
|Voltage   I(typ)   I(min)   I(max)
-2.5V     -2.99A     -2.35A     -4.091A
-1.123V   -455.1mA   -463.2mA   -453.7mA
-1.072V   -370.5mA   -399.5mA   -336.3mA
-1.021V   -289.2mA   -337.4mA   -228.6mA
-970mV    -212.6mA   -277.4mA   -140mA
-919mV    -143.6mA   -220.1mA   -87.4mA
-868mV    -87.39mA   -166.5mA   -68.45mA
-817mV    -50.94mA   -117.8mA   -59.13mA
-715mV    -24.99mA   -42.37mA   -39.7mA
-562mV    -7.608mA   -4.125mA   -12.95mA
-307mV    -97.66uA   -51.76uA   -173.8uA
5V        114uA      49.34uA    266.8uA
[POWER_clamp]
|Voltage   I(typ)   I(min)   I(max)
-2.5V     22.27uA    8.76uA     64.97uA
-2.141V   14.03uA    4.838uA    43.67uA
-1.835V   8.45uA     2.288uA    28.47uA
-1.58V    4.901uA    735.9nA    18.31uA
-1.274V   1.887uA    -485.7nA   9.321uA
-1.07V    594.4nA    -924nA     5.173uA
-1.019V   355.1nA    -987.6nA   4.351uA
-917mV    -26.38nA   -1.058uA   2.951uA
-764mV    -358.6nA   -1.065uA   1.434uA
-509mV    -424.7nA   -1.065uA   291.6nA
-101mV    -424.7nA   -1.065uA   0A
2.5V      -424.7nA   -1.065uA   0A
[Ramp]
| variable   typ   min   max
dV/dt_r   0.976/0.234n   0.768/0.347n   1.223/0.127n
dV/dt_f   1.052/0.218n   0.802/0.327n   1.263/0.135n
R_load = 50.000
[Rising Waveform]
R_fixture= 50.000
V_fixture= 0.0
V_fixture_min= 0.0
V_fixture_max= 0.0
|time   V(typ)   V(min)   V(max)
0s        4.486nV    34.65nV    14.98nV
595ps     43.37uV    -3.403uV   -32.25mV
795ps     -305uV     -3.403uV   1.71V
1.052ns   -22.13mV   21.4uV     1.966V
1.278ns   1.092V     -132.6uV   2.004V
1.723ns   1.547V     -25.33mV   2.029V
2.03ns    1.588V     804.3mV    2.034V
2.278ns   1.605V     1.091V     2.036V
3.181ns   1.624V     1.251V     2.037V
20ns      1.627V     1.28V      2.038V
[Rising Waveform]
R_fixture= 50.000
V_fixture= 2.500
V_fixture_min= 2.380
V_fixture_max= 2.630
|time   V(typ)   V(min)   V(max)
0s        745.3mV    1.043V     522.1mV
552ps     745.3mV    1.043V     540.2mV
719ps     746mV      1.043V     2.365V
938ps     792.7mV    1.043V     2.58V
1.061ns   1.463V     1.043V     2.598V
1.261ns   2.374V     1.044V     2.612V
1.493ns   2.458V     1.081V     2.62V
1.89ns    2.484V     2.21V      2.625V
2.254ns   2.492V     2.352V     2.627V
20ns      2.499V     2.379V     2.628V
[Falling Waveform]
R_fixture= 50.000
V_fixture= 2.500
V_fixture_min= 2.380
V_fixture_max= 2.630
|time   V(typ)   V(min)   V(max)
0s        2.499V     2.379V     2.628V
608ps     2.499V     2.379V     2.682V
832ps     2.499V     2.379V     802.1mV
1.093ns   2.542V     2.379V     568.6mV
1.179ns   2.074V     2.379V     555.6mV
1.422ns   1.021V     2.38V      536.2mV
2.008ns   770.4mV    2.01V      524.2mV
2.387ns   755.5mV    1.237V     522.6mV
3.224ns   746.6mV    1.065V     522.1mV
20ns      745.3mV    1.043V     522.1mV
[Falling Waveform]
R_fixture= 50.000
V_fixture= 0.0
V_fixture_min= 0.0
V_fixture_max= 0.0
|time   V(typ)   V(min)   V(max)
0s        1.627V     1.28V      2.038V
584ps     1.627V     1.28V      2.025V
731ps     1.627V     1.28V      263.5mV
1.05ns    1.49V      1.28V      23.71mV
1.26ns    179.2mV    1.28V      11.29mV
1.641ns   19.76mV    1.285V     2.947mV
1.764ns   15.48mV    1.135V     1.939mV
2.052ns   6.313mV    176.8mV    730.9uV
2.383ns   2.725mV    25.24mV    294.7uV
20ns      43.56nV    83.03nV    -176.6nV
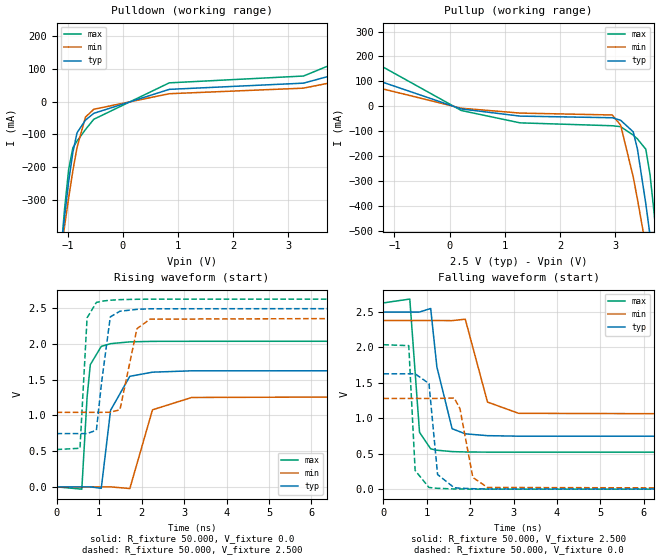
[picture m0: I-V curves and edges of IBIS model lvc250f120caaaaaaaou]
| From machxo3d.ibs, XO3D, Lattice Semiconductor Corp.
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|   Model lvc250f120caaaaaaaou
[Model] lvc250f120caaaaaaaou
Model_type Output
Polarity   Non-Inverting
Enable   Active-High
Vmeas =  1.250V
Cref =  0.0F
Rref =  1.000M
Vref =  0.0V
C_comp   4.200pF   3.800pF   7.500pF
[Temperature Range]   25.000   0.105k   -40.000
[Voltage Range]   2.500V   2.380V   2.630V
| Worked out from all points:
|   slope of the pulldown table from 0 to 0.375 V, typ, clamps not added: 18.1 ohm
|   slope of the pullup table from 0 to 0.375 V, typ, clamps not added: 21.7 ohm
|   rising waveform, R_fixture 50.000, V_fixture 0.0: 20-80 % time 235ps typ, 349ps min, 127ps max; typ from 0 V to 1.63 V
|   rising waveform, R_fixture 50.000, V_fixture 2.500: 20-80 % time 161ps typ, 259ps min, 87.7ps max; typ from 0.745 V to 2.5 V
|   falling waveform, R_fixture 50.000, V_fixture 2.500: 20-80 % time 218ps typ, 326ps min, 135ps max; typ from 2.5 V to 0.745 V
|   falling waveform, R_fixture 50.000, V_fixture 0.0: 20-80 % time 131ps typ, 212ps min, 80.7ps max; typ from 1.63 V to 0 V
[Pulldown]
|Voltage   I(typ)   I(min)   I(max)
-2.5V     -2.991A    -2.351A    -4.092A
-1.132V   -477.3mA   -478.1mA   -490.2mA
-1.056V   -355.1mA   -384.2mA   -331.9mA
-980mV    -245mA     -294.8mA   -207.8mA
-904mV    -155.4mA   -212.2mA   -141.8mA
-828mV    -95.45mA   -140.5mA   -121mA
-676mV    -56.82mA   -47.75mA   -85.79mA
-524mV    -35.97mA   -23.54mA   -54.16mA
844mV     37.4mA     24.05mA    57.34mA
3.276V    56.42mA    41.07mA    78.25mA
4.112V    94.74mA    69.13mA    135.9mA
5V        151mA      107.3mA    226.6mA
[Pullup]
|Voltage   I(typ)   I(min)   I(max)
-2.5V     193.8mA    140.3mA    316.6mA
212mV     -10.29mA   -7.409mA   -16.56mA
1.276V    -39.03mA   -26.89mA   -66.04mA
2.948V    -45.59mA   -34.5mA    -77.68mA
3.1V      -55.75mA   -75.34mA   -81.35mA
3.328V    -102mA     -282.8mA   -115.2mA
3.404V    -170.8mA   -371.6mA   -130.5mA
3.556V    -390.2mA   -561.5mA   -171.8mA
3.632V    -516.1mA   -660.2mA   -272.6mA
3.708V    -646.8mA   -760.5mA   -430.1mA
3.784V    -780.5mA   -862mA     -608.4mA
5V        -3.038A    -2.551A    -3.824A
[Ramp]
| variable   typ   min   max
dV/dt_r   0.976/0.234n   0.768/0.347n   1.223/0.127n
dV/dt_f   1.052/0.218n   0.802/0.327n   1.263/0.135n
R_load = 50.000
[Rising Waveform]
R_fixture= 50.000
V_fixture= 0.0
V_fixture_min= 0.0
V_fixture_max= 0.0
|time   V(typ)   V(min)   V(max)
0s        4.486nV    34.65nV    14.98nV
595ps     40.5uV     -5.822uV   -32.25mV
719ps     122.8uV    -5.822uV   1.255V
795ps     -302.7uV   -5.822uV   1.71V
1.053ns   -20.18mV   18.99uV    1.966V
1.272ns   1.072V     -130.5uV   2.004V
1.725ns   1.547V     -23.52mV   2.029V
2.258ns   1.605V     1.078V     2.036V
3.181ns   1.624V     1.251V     2.037V
20ns      1.627V     1.28V      2.038V
[Rising Waveform]
R_fixture= 50.000
V_fixture= 2.500
V_fixture_min= 2.380
V_fixture_max= 2.630
|time   V(typ)   V(min)   V(max)
0s        745.3mV    1.043V     522.1mV
552ps     745.3mV    1.043V     540.2mV
719ps     746mV      1.043V     2.365V
938ps     792.7mV    1.043V     2.581V
1.062ns   1.47V      1.043V     2.598V
1.265ns   2.378V     1.044V     2.612V
1.492ns   2.458V     1.079V     2.62V
1.892ns   2.484V     2.213V     2.625V
2.2ns     2.492V     2.347V     2.627V
20ns      2.499V     2.379V     2.628V
[Falling Waveform]
R_fixture= 50.000
V_fixture= 2.500
V_fixture_min= 2.380
V_fixture_max= 2.630
|time   V(typ)   V(min)   V(max)
0s        2.499V     2.379V     2.628V
608ps     2.499V     2.379V     2.682V
832ps     2.499V     2.379V     802.1mV
1.089ns   2.549V     2.379V     569.3mV
1.232ns   1.724V     2.379V     549.4mV
1.583ns   852.9mV    2.378V     530mV
1.886ns   780.6mV    2.398V     524.9mV
2.398ns   754.9mV    1.229V     522.6mV
3.114ns   747.5mV    1.07V      522.1mV
20ns      745.3mV    1.043V     522.1mV
[Falling Waveform]
R_fixture= 50.000
V_fixture= 0.0
V_fixture_min= 0.0
V_fixture_max= 0.0
|time   V(typ)   V(min)   V(max)
0s        1.627V     1.28V      2.038V
584ps     1.627V     1.28V      2.025V
731ps     1.627V     1.28V      263.5mV
1.05ns    1.49V      1.28V      23.5mV
1.248ns   206.8mV    1.28V      11.94mV
1.632ns   19.96mV    1.286V     2.869mV
1.764ns   13.8mV     1.135V     1.864mV
2.06ns    6.306mV    165.2mV    693.8uV
2.399ns   2.657mV    23.85mV    276.6uV
20ns      -323.9nV   92.49nV    -312.8nV
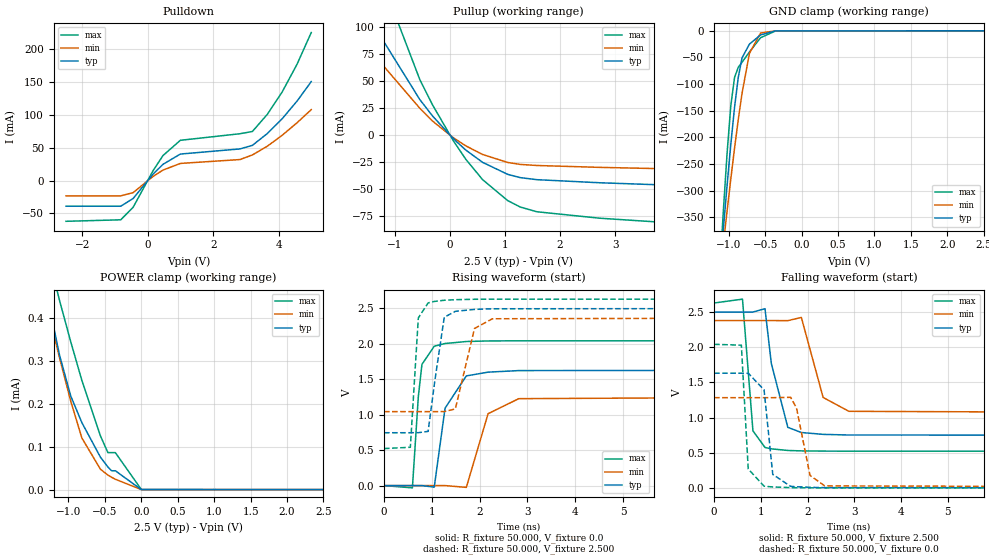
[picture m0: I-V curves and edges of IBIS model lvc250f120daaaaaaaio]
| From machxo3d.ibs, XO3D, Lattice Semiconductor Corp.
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|   Model lvc250f120daaaaaaaio
[Model] lvc250f120daaaaaaaio
Model_type I/O
Polarity   Non-Inverting
Enable   Active-Low
Vinl =  0.700V
Vinh =  1.700V
Vmeas =  1.250V
Cref =  0.0F
Rref =  1.000M
Vref =  0.0V
C_comp   4.200pF   3.800pF   7.500pF
[Temperature Range]   25.000   0.105k   -40.000
[Voltage Range]   2.500V   2.380V   2.630V
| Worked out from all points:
|   slope of the pulldown table from 0 to 0.375 V, typ, clamps not added: 18.1 ohm
|   slope of the pullup table from 0 to 0.375 V, typ, clamps not added: 21.7 ohm
|   GND clamp passes 1 mA (typ) near -0.43 V on its own axis
|   POWER clamp passes 1 mA (typ) near -1.90 V on its own axis
|   rising waveform, R_fixture 50.000, V_fixture 0.0: 20-80 % time 236ps typ, 350ps min, 128ps max; typ from 0 V to 1.63 V
|   rising waveform, R_fixture 50.000, V_fixture 2.500: 20-80 % time 161ps typ, 260ps min, 87.9ps max; typ from 0.745 V to 2.5 V
|   falling waveform, R_fixture 50.000, V_fixture 2.500: 20-80 % time 220ps typ, 332ps min, 137ps max; typ from 2.5 V to 0.745 V
|   falling waveform, R_fixture 50.000, V_fixture 0.0: 20-80 % time 130ps typ, 212ps min, 81.3ps max; typ from 1.63 V to 0 V
[Pulldown]
|Voltage   I(typ)   I(min)   I(max)
-2.5V     -39.23mA   -23.44mA   -62.24mA
-828mV    -39.23mA   -23.44mA   -59.96mA
-448mV    -27.42mA   -18.49mA   -40.8mA
160mV     9.666mA    6.229mA    14.91mA
464mV     24.66mA    15.88mA    38.02mA
996mV     40.36mA    26.05mA    61.35mA
2.82V     48.17mA    31.96mA    71.35mA
3.2V      53.6mA     39.02mA    74.8mA
3.656V    71.67mA    52.31mA    100.9mA
4.112V    94.28mA    69.02mA    135.2mA
4.568V    121.3mA    88.22mA    177.6mA
5V        150.9mA    108.1mA    225.7mA
[Pullup]
|Voltage   I(typ)   I(min)   I(max)
-2.5V     193.8mA    140.9mA    315.8mA
-1.612V   120mA      87.95mA    193mA
-548mV    32.97mA    24.93mA    51.38mA
-320mV    17.99mA    13.25mA    28.31mA
60mV      -3.106mA   -2.235mA   -5.004mA
288mV     -13.72mA   -9.814mA   -22.24mA
592mV     -25.01mA   -17.73mA   -40.97mA
1.048V    -36.09mA   -25.12mA   -60.34mA
1.276V    -39.13mA   -26.93mA   -66.27mA
1.58V     -41.03mA   -27.92mA   -70.68mA
2.72V     -43.87mA   -29.66mA   -76.62mA
5V        -47.88mA   -32.11mA   -84.21mA
[GND_clamp]
|Voltage   I(typ)   I(min)   I(max)
-2.5V     -2.99A     -2.35A     -4.091A
-1.123V   -455.1mA   -463.2mA   -453.7mA
-1.072V   -370.5mA   -399.5mA   -336.3mA
-1.021V   -289.2mA   -337.4mA   -228.6mA
-970mV    -212.6mA   -277.4mA   -140mA
-919mV    -143.6mA   -220.1mA   -87.4mA
-868mV    -87.39mA   -166.5mA   -68.45mA
-817mV    -50.94mA   -117.8mA   -59.13mA
-715mV    -24.99mA   -42.37mA   -39.7mA
-562mV    -7.608mA   -4.125mA   -12.95mA
-358mV    -194.9uA   -98.36uA   -303.6uA
2.5V      13.17nA    0A         -19.29uA
[POWER_clamp]
|Voltage   I(typ)   I(min)   I(max)
-2.5V     1.538mA    1.365mA    2.125mA
-1.325V   482.6uA    450.2uA    591.5uA
-1.274V   438.4uA    413.8uA    546.6uA
-1.121V   313.5uA    307.1uA    441uA
-968mV    218.6uA    206.5uA    345.2uA
-815mV    156.3uA    120.3uA    254.8uA
-560mV    75.6uA     47.55uA    125.2uA
-458mV    52.75uA    33.88uA    86.35uA
-407mV    44.01uA    28.68uA    86.35uA
-356mV    44.01uA    24.21uA    86.35uA
1mV       0A         0A         141nA
2.5V      0A         0A         0A
[Ramp]
| variable   typ   min   max
dV/dt_r   0.979/0.235n   0.770/0.349n   1.225/0.128n
dV/dt_f   1.053/0.220n   0.802/0.330n   1.265/0.136n
R_load = 50.000
[Rising Waveform]
R_fixture= 50.000
V_fixture= 0.0
V_fixture_min= 0.0
V_fixture_max= 0.0
|time   V(typ)   V(min)   V(max)
0s        4.486nV    34.65nV    14.98nV
595ps     43.35uV    -3.423uV   -32.25mV
719ps     128.6uV    -3.423uV   1.255V
795ps     -294.1uV   -3.423uV   1.71V
1.052ns   -22.13mV   21.4uV     1.966V
1.278ns   1.092V     -133.7uV   2.004V
1.723ns   1.547V     -25.33mV   2.032V
2.178ns   1.6V       1.014V     2.04V
2.82ns    1.622V     1.226V     2.042V
20ns      1.631V     1.283V     2.042V
[Rising Waveform]
R_fixture= 50.000
V_fixture= 2.500
V_fixture_min= 2.380
V_fixture_max= 2.630
|time   V(typ)   V(min)   V(max)
0s        745.3mV    1.043V     522.1mV
552ps     745.3mV    1.043V     540.2mV
719ps     746mV      1.043V     2.365V
924ps     764.5mV    1.043V     2.577V
1.061ns   1.463V     1.043V     2.598V
1.261ns   2.374V     1.044V     2.614V
1.493ns   2.458V     1.081V     2.622V
1.894ns   2.485V     2.216V     2.628V
2.267ns   2.494V     2.353V     2.629V
20ns      2.5V       2.38V      2.63V
[Falling Waveform]
R_fixture= 50.000
V_fixture= 2.500
V_fixture_min= 2.380
V_fixture_max= 2.630
|time   V(typ)   V(min)   V(max)
0s        2.5V       2.38V      2.63V
608ps     2.5V       2.38V      2.685V
832ps     2.501V     2.38V      811.3mV
1.09ns    2.549V     2.38V      574.3mV
1.225ns   1.771V     2.38V      555.1mV
1.578ns   861.1mV    2.379V     532mV
1.868ns   787.4mV    2.424V     526mV
2.334ns   761mV      1.286V     522.9mV
2.886ns   751.9mV    1.089V     522.2mV
20ns      745.3mV    1.043V     522mV
[Falling Waveform]
R_fixture= 50.000
V_fixture= 0.0
V_fixture_min= 0.0
V_fixture_max= 0.0
|time   V(typ)   V(min)   V(max)
0s        1.631V     1.283V     2.042V
584ps     1.631V     1.283V     2.03V
731ps     1.631V     1.283V     269.7mV
1.07ns    1.394V     1.283V     23.76mV
1.256ns   191.6mV    1.283V     13mV
1.639ns   21.14mV    1.288V     3.369mV
1.764ns   16.03mV    1.138V     1.991mV
2.053ns   7.739mV    177.7mV    772.6uV
2.369ns   3.241mV    27.65mV    324.2uV
20ns      -45.86nV   119.6nV    -267.7nV
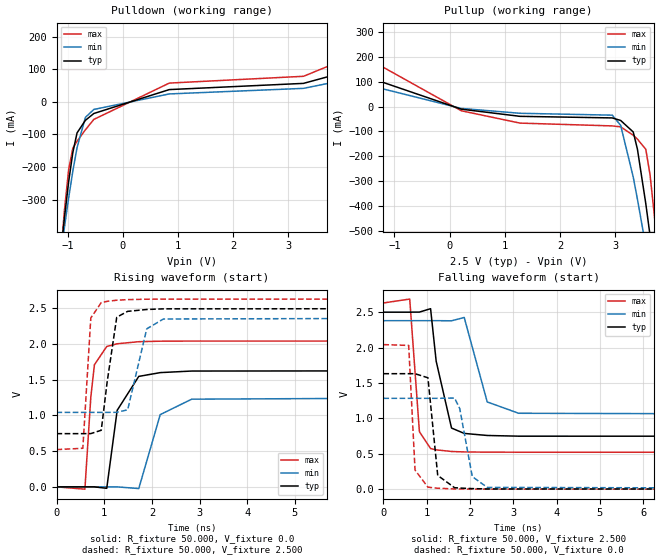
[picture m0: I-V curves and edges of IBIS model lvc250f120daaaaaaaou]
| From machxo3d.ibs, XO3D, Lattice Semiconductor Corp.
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|   Model lvc250f120daaaaaaaou
[Model] lvc250f120daaaaaaaou
Model_type Output
Polarity   Non-Inverting
Enable   Active-High
Vmeas =  1.250V
Cref =  0.0F
Rref =  1.000M
Vref =  0.0V
C_comp   4.200pF   3.800pF   7.500pF
[Temperature Range]   25.000   0.105k   -40.000
[Voltage Range]   2.500V   2.380V   2.630V
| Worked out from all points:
|   slope of the pulldown table from 0 to 0.375 V, typ, clamps not added: 18.1 ohm
|   slope of the pullup table from 0 to 0.375 V, typ, clamps not added: 21.7 ohm
|   rising waveform, R_fixture 50.000, V_fixture 0.0: 20-80 % time 236ps typ, 352ps min, 128ps max; typ from 0 V to 1.63 V
|   rising waveform, R_fixture 50.000, V_fixture 2.500: 20-80 % time 161ps typ, 259ps min, 87.9ps max; typ from 0.745 V to 2.5 V
|   falling waveform, R_fixture 50.000, V_fixture 2.500: 20-80 % time 220ps typ, 330ps min, 137ps max; typ from 2.5 V to 0.745 V
|   falling waveform, R_fixture 50.000, V_fixture 0.0: 20-80 % time 131ps typ, 212ps min, 81.4ps max; typ from 1.63 V to 0 V
[Pulldown]
|Voltage   I(typ)   I(min)   I(max)
-2.5V     -2.991A    -2.351A    -4.092A
-1.132V   -477.3mA   -478.1mA   -490.2mA
-1.056V   -355.1mA   -384.2mA   -331.9mA
-980mV    -245mA     -294.8mA   -207.8mA
-904mV    -155.4mA   -212.2mA   -141.8mA
-828mV    -95.45mA   -140.5mA   -121mA
-676mV    -56.82mA   -47.75mA   -85.79mA
-524mV    -35.97mA   -23.54mA   -54.16mA
844mV     37.4mA     24.05mA    57.34mA
3.276V    56.41mA    41.13mA    78.15mA
4.112V    95.01mA    69.77mA    136mA
5V        152.4mA    109.5mA    227.6mA
[Pullup]
|Voltage   I(typ)   I(min)   I(max)
-2.5V     195.3mA    142.3mA    317.9mA
212mV     -10.41mA   -7.459mA   -16.84mA
1.276V    -39.2mA    -26.97mA   -66.41mA
2.948V    -45.59mA   -34.5mA    -77.68mA
3.1V      -55.75mA   -75.34mA   -81.35mA
3.328V    -102mA     -282.8mA   -115.2mA
3.404V    -170.8mA   -371.6mA   -130.5mA
3.556V    -390.2mA   -561.5mA   -171.8mA
3.632V    -516.1mA   -660.2mA   -272.6mA
3.708V    -646.8mA   -760.5mA   -430.1mA
3.784V    -780.5mA   -862mA     -608.4mA
5V        -3.038A    -2.551A    -3.824A
[Ramp]
| variable   typ   min   max
dV/dt_r   0.979/0.235n   0.770/0.349n   1.225/0.128n
dV/dt_f   1.053/0.220n   0.802/0.330n   1.265/0.136n
R_load = 50.000
[Rising Waveform]
R_fixture= 50.000
V_fixture= 0.0
V_fixture_min= 0.0
V_fixture_max= 0.0
|time   V(typ)   V(min)   V(max)
0s        4.486nV    34.65nV    14.98nV
595ps     40.5uV     -5.846uV   -32.25mV
719ps     122.8uV    -5.846uV   1.255V
795ps     -302.7uV   -5.846uV   1.71V
1.053ns   -20.18mV   18.99uV    1.966V
1.272ns   1.072V     -128.2uV   2.004V
1.725ns   1.547V     -23.52mV   2.033V
2.175ns   1.6V       1.012V     2.04V
2.835ns   1.622V     1.228V     2.042V
20ns      1.631V     1.283V     2.042V
[Rising Waveform]
R_fixture= 50.000
V_fixture= 2.500
V_fixture_min= 2.380
V_fixture_max= 2.630
|time   V(typ)   V(min)   V(max)
0s        745.3mV    1.043V     522.1mV
552ps     745.3mV    1.043V     540.2mV
719ps     746mV      1.043V     2.365V
938ps     792.7mV    1.043V     2.581V
1.062ns   1.47V      1.043V     2.598V
1.263ns   2.376V     1.044V     2.614V
1.492ns   2.458V     1.079V     2.622V
1.892ns   2.484V     2.213V     2.628V
2.242ns   2.493V     2.351V     2.629V
20ns      2.5V       2.38V      2.63V
[Falling Waveform]
R_fixture= 50.000
V_fixture= 2.500
V_fixture_min= 2.380
V_fixture_max= 2.630
|time   V(typ)   V(min)   V(max)
0s        2.5V       2.38V      2.63V
608ps     2.5V       2.38V      2.685V
832ps     2.501V     2.38V      811.2mV
1.09ns    2.549V     2.38V      574.3mV
1.219ns   1.808V     2.38V      555.3mV
1.574ns   863.3mV    2.378V     532.3mV
1.867ns   787.5mV    2.425V     525.9mV
2.399ns   758.3mV    1.232V     522.7mV
3.123ns   748.6mV    1.072V     522.1mV
20ns      745.3mV    1.043V     522mV
[Falling Waveform]
R_fixture= 50.000
V_fixture= 0.0
V_fixture_min= 0.0
V_fixture_max= 0.0
|time   V(typ)   V(min)   V(max)
0s        1.631V     1.283V     2.042V
584ps     1.631V     1.283V     2.03V
731ps     1.631V     1.283V     269.7mV
1.029ns   1.573V     1.283V     27.83mV
1.255ns   193.9mV    1.283V     13.05mV
1.644ns   20.63mV    1.287V     3.069mV
1.764ns   16mV       1.138V     2.063mV
2.053ns   8.097mV    177.7mV    808.6uV
2.4ns     3.168mV    24.81mV    240.4uV
20ns      -70.91nV   125.4nV    30.23nV
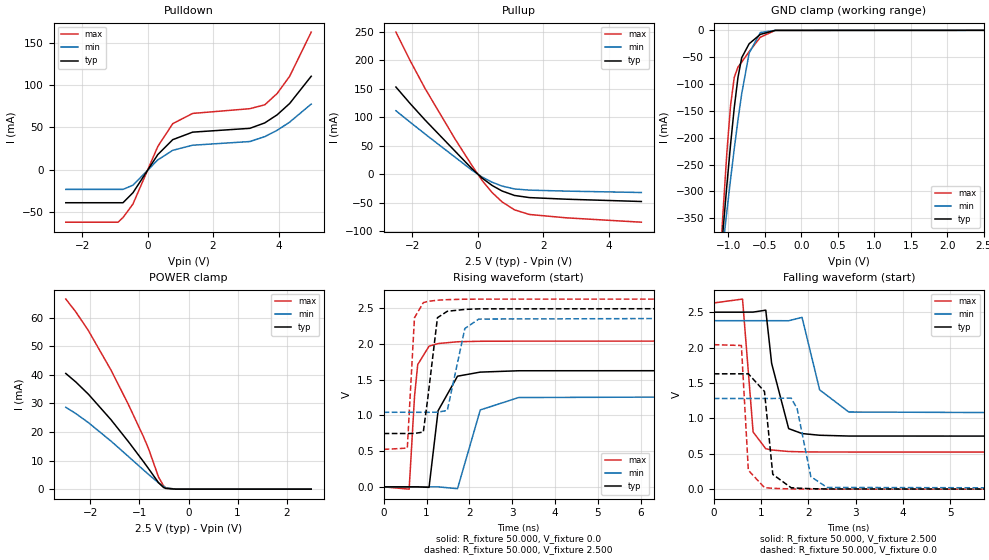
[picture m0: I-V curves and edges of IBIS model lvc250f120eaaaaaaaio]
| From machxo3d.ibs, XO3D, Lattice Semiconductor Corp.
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|   Model lvc250f120eaaaaaaaio
[Model] lvc250f120eaaaaaaaio
Model_type I/O
Polarity   Non-Inverting
Enable   Active-Low
Vinl =  0.700V
Vinh =  1.700V
Vmeas =  1.250V
Cref =  0.0F
Rref =  1.000M
Vref =  0.0V
C_comp   4.200pF   3.800pF   7.500pF
[Temperature Range]   25.000   0.105k   -40.000
[Voltage Range]   2.500V   2.380V   2.630V
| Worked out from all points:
|   slope of the pulldown table from 0 to 0.375 V, typ, clamps not added: 18.1 ohm
|   slope of the pullup table from 0 to 0.375 V, typ, clamps not added: 21.7 ohm
|   GND clamp passes 1 mA (typ) near -0.43 V on its own axis
|   POWER clamp passes 1 mA (typ) near -0.54 V on its own axis
|   rising waveform, R_fixture 50.000, V_fixture 0.0: 20-80 % time 235ps typ, 349ps min, 127ps max; typ from 0 V to 1.63 V
|   rising waveform, R_fixture 50.000, V_fixture 2.500: 20-80 % time 161ps typ, 258ps min, 87.7ps max; typ from 0.747 V to 2.5 V
|   falling waveform, R_fixture 50.000, V_fixture 2.500: 20-80 % time 218ps typ, 325ps min, 136ps max; typ from 2.5 V to 0.747 V
|   falling waveform, R_fixture 50.000, V_fixture 0.0: 20-80 % time 130ps typ, 212ps min, 81.1ps max; typ from 1.63 V to 0 V
[Pulldown]
|Voltage   I(typ)   I(min)   I(max)
-2.5V     -39.23mA   -23.44mA   -62.24mA
-904mV    -39.23mA   -23.44mA   -62.24mA
-752mV    -39.23mA   -23.44mA   -56.76mA
-448mV    -27.42mA   -18.49mA   -40.8mA
312mV     17.71mA    11.41mA    27.31mA
768mV     35.33mA    22.74mA    54.24mA
1.376V    44.21mA    28.76mA    66.35mA
3.124V    48.72mA    33.11mA    71.94mA
3.58V     55.12mA    38.9mA     76.54mA
3.96V     64.74mA    46.41mA    89.97mA
4.34V     78.07mA    56.04mA    110.2mA
5V        110.3mA    77.42mA    162.5mA
[Pullup]
|Voltage   I(typ)   I(min)   I(max)
-2.5V     153.1mA    111.5mA    249.6mA
-2.068V   124.3mA    91.56mA    199.8mA
-1.612V   95.34mA    70.73mA    150.8mA
-700mV    40.91mA    30.25mA    62.53mA
-168mV    9.171mA    6.69mA     14.58mA
136mV     -6.852mA   -4.921mA   -11.06mA
440mV     -19.77mA   -14.08mA   -32.21mA
744mV     -29.47mA   -20.78mA   -48.57mA
1.124V    -37.28mA   -25.86mA   -62.59mA
1.58V     -41.03mA   -27.92mA   -70.68mA
2.72V     -43.87mA   -29.66mA   -76.62mA
5V        -47.88mA   -32.11mA   -84.22mA
[GND_clamp]
|Voltage   I(typ)   I(min)   I(max)
-2.5V     -2.99A     -2.35A     -4.091A
-1.123V   -455.1mA   -463.2mA   -453.6mA
-1.072V   -370.5mA   -399.5mA   -336.3mA
-1.021V   -289.1mA   -337.4mA   -228.5mA
-970mV    -212.6mA   -277.3mA   -139.9mA
-919mV    -143.6mA   -220.1mA   -87.34mA
-868mV    -87.35mA   -166.5mA   -68.39mA
-817mV    -50.9mA    -117.8mA   -59.07mA
-715mV    -24.94mA   -42.34mA   -39.63mA
-562mV    -7.547mA   -4.077mA   -12.85mA
-358mV    -114uA     -53.77uA   -172.8uA
2.5V      0A         0A         0A
[POWER_clamp]
|Voltage   I(typ)   I(min)   I(max)
-2.5V     40.49mA    28.66mA    66.53mA
-2.294V   37.48mA    26.44mA    61.99mA
-2.039V   33.22mA    23.28mA    55.47mA
-1.58V    24.32mA    16.83mA    41.7mA
-1.223V   16.6mA     11.41mA    29.58mA
-917mV    9.616mA    6.712mA    18.32mA
-815mV    7.205mA    5.171mA    14.19mA
-611mV    2.275mA    2.213mA    4.254mA
-509mV    589.4uA    929.1uA    1.152mA
-458mV    232.9uA    445.2uA    427.7uA
-254mV    3.785uA    4.472uA    4.114uA
2.5V      0A         0A         3.667nA
[Ramp]
| variable   typ   min   max
dV/dt_r   0.978/0.234n   0.769/0.347n   1.225/0.127n
dV/dt_f   1.052/0.218n   0.801/0.327n   1.263/0.135n
R_load = 50.000
[Rising Waveform]
R_fixture= 50.000
V_fixture= 0.0
V_fixture_min= 0.0
V_fixture_max= 0.0
|time   V(typ)   V(min)   V(max)
0s        4.635nV    35nV       15.53nV
595ps     43.38uV    -3.382uV   -32.32mV
720ps     130.6uV    -3.382uV   1.265V
795ps     -291.9uV   -3.382uV   1.713V
1.059ns   -6.969mV   21.42uV    1.97V
1.27ns    1.066V     -125.6uV   2.007V
1.723ns   1.55V      -25.4mV    2.032V
2.254ns   1.607V     1.077V     2.039V
3.149ns   1.626V     1.251V     2.041V
20ns      1.629V     1.281V     2.041V
[Rising Waveform]
R_fixture= 50.000
V_fixture= 2.500
V_fixture_min= 2.380
V_fixture_max= 2.630
|time   V(typ)   V(min)   V(max)
0s        747.2mV    1.044V     524.3mV
552ps     747.2mV    1.045V     542.8mV
719ps     747.9mV    1.044V     2.368V
925ps     768.1mV    1.044V     2.58V
1.028ns   1.233V     1.044V     2.597V
1.255ns   2.369V     1.046V     2.614V
1.485ns   2.459V     1.069V     2.622V
1.894ns   2.485V     2.217V     2.628V
2.219ns   2.493V     2.35V      2.629V
20ns      2.5V       2.38V      2.63V
[Falling Waveform]
R_fixture= 50.000
V_fixture= 2.500
V_fixture_min= 2.380
V_fixture_max= 2.630
|time   V(typ)   V(min)   V(max)
0s        2.5V       2.38V      2.63V
608ps     2.5V       2.38V      2.685V
832ps     2.501V     2.38V      807.8mV
1.1ns     2.528V     2.38V      571.2mV
1.224ns   1.776V     2.38V      553.4mV
1.584ns   855mV      2.379V     532.2mV
1.867ns   785.6mV    2.426V     527.3mV
2.239ns   761.4mV    1.403V     525.1mV
2.855ns   750.4mV    1.09V      524.5mV
20ns      747.2mV    1.044V     524.3mV
[Falling Waveform]
R_fixture= 50.000
V_fixture= 0.0
V_fixture_min= 0.0
V_fixture_max= 0.0
|time   V(typ)   V(min)   V(max)
0s        1.629V     1.281V     2.041V
584ps     1.629V     1.281V     2.029V
731ps     1.629V     1.281V     267.1mV
1.072ns   1.38V      1.281V     22.15mV
1.248ns   208.7mV    1.281V     11.97mV
1.636ns   20.24mV    1.287V     2.928mV
1.764ns   15.04mV    1.136V     1.927mV
2.053ns   6.833mV    176.2mV    727.5uV
2.396ns   2.69mV     24.31mV    292.6uV
20ns      -14.9nV    96.1nV     -125nV
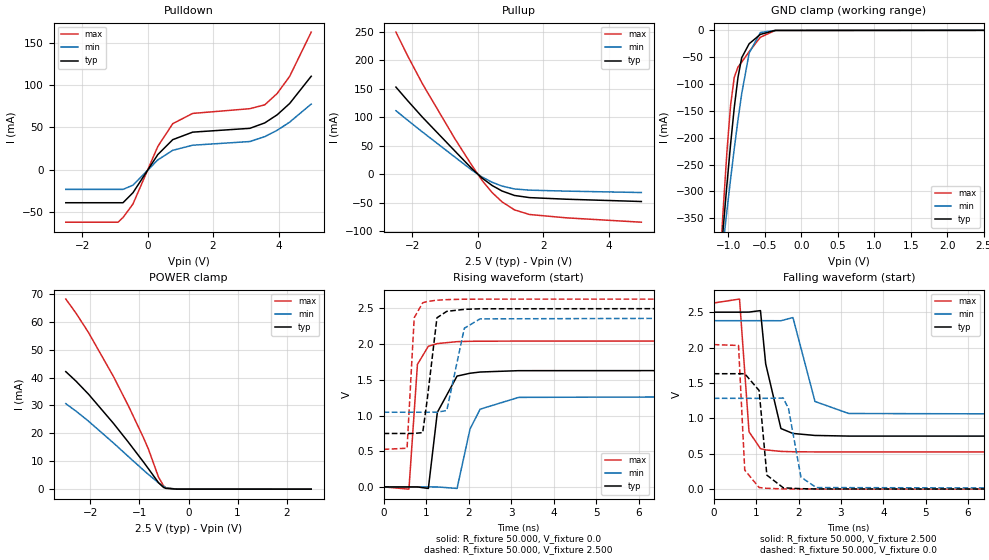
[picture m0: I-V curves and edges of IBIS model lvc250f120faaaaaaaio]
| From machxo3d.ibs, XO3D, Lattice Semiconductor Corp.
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|   Model lvc250f120faaaaaaaio
[Model] lvc250f120faaaaaaaio
Model_type I/O
Polarity   Non-Inverting
Enable   Active-Low
Vinl =  0.700V
Vinh =  1.700V
Vmeas =  1.250V
Cref =  0.0F
Rref =  1.000M
Vref =  0.0V
C_comp   4.200pF   3.800pF   7.500pF
[Temperature Range]   25.000   0.105k   -40.000
[Voltage Range]   2.500V   2.380V   2.630V
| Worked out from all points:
|   slope of the pulldown table from 0 to 0.375 V, typ, clamps not added: 18.1 ohm
|   slope of the pullup table from 0 to 0.375 V, typ, clamps not added: 21.7 ohm
|   GND clamp passes 1 mA (typ) near -0.43 V on its own axis
|   POWER clamp passes 1 mA (typ) near -0.54 V on its own axis
|   rising waveform, R_fixture 50.000, V_fixture 0.0: 20-80 % time 234ps typ, 347ps min, 127ps max; typ from 0.001 V to 1.63 V
|   rising waveform, R_fixture 50.000, V_fixture 2.500: 20-80 % time 160ps typ, 260ps min, 87.6ps max; typ from 0.749 V to 2.5 V
|   falling waveform, R_fixture 50.000, V_fixture 2.500: 20-80 % time 219ps typ, 327ps min, 136ps max; typ from 2.5 V to 0.749 V
|   falling waveform, R_fixture 50.000, V_fixture 0.0: 20-80 % time 130ps typ, 212ps min, 81.2ps max; typ from 1.63 V to 0.001 V
[Pulldown]
|Voltage   I(typ)   I(min)   I(max)
-2.5V     -39.23mA   -23.44mA   -62.24mA
-904mV    -39.23mA   -23.44mA   -62.24mA
-752mV    -39.23mA   -23.44mA   -56.76mA
-448mV    -27.42mA   -18.49mA   -40.8mA
312mV     17.71mA    11.41mA    27.31mA
768mV     35.33mA    22.74mA    54.24mA
1.376V    44.21mA    28.76mA    66.35mA
3.124V    48.72mA    33.11mA    71.94mA
3.58V     55.12mA    38.9mA     76.53mA
3.96V     64.74mA    46.41mA    89.96mA
4.34V     78.06mA    56.04mA    110.1mA
5V        110.3mA    77.43mA    162.5mA
[Pullup]
|Voltage   I(typ)   I(min)   I(max)
-2.5V     153.1mA    111.6mA    249.7mA
-2.144V   129.4mA    95.09mA    208.3mA
-1.688V   100.1mA    74.19mA    158.7mA
-700mV    40.91mA    30.25mA    62.53mA
-168mV    9.171mA    6.69mA     14.58mA
136mV     -6.852mA   -4.921mA   -11.06mA
440mV     -19.77mA   -14.08mA   -32.21mA
744mV     -29.47mA   -20.78mA   -48.57mA
1.124V    -37.28mA   -25.86mA   -62.59mA
1.58V     -41.03mA   -27.92mA   -70.68mA
2.72V     -43.87mA   -29.66mA   -76.62mA
5V        -47.88mA   -32.11mA   -84.21mA
[GND_clamp]
|Voltage   I(typ)   I(min)   I(max)
-2.5V     -2.99A     -2.35A     -4.091A
-1.123V   -455.1mA   -463.2mA   -453.7mA
-1.072V   -370.5mA   -399.5mA   -336.3mA
-1.021V   -289.2mA   -337.4mA   -228.6mA
-970mV    -212.6mA   -277.4mA   -140mA
-919mV    -143.6mA   -220.1mA   -87.39mA
-868mV    -87.38mA   -166.5mA   -68.44mA
-817mV    -50.93mA   -117.8mA   -59.12mA
-715mV    -24.98mA   -42.36mA   -39.69mA
-562mV    -7.596mA   -4.111mA   -12.93mA
-358mV    -193.4uA   -101.2uA   -309.3uA
2.5V      13.17nA    0A         -19.29uA
[POWER_clamp]
|Voltage   I(typ)   I(min)   I(max)
-2.5V     42.14mA    30.66mA    68.15mA
-2.294V   38.75mA    27.99mA    63.15mA
-2.039V   34.09mA    24.4mA     56.2mA
-1.529V   23.59mA    16.56mA    40.38mA
-1.223V   16.79mA    11.66mA    29.8mA
-917mV    9.72mA     6.817mA    18.42mA
-815mV    7.285mA    5.246mA    14.27mA
-611mV    2.32mA     2.253mA    4.314mA
-509mV    627.1uA    959.6uA    1.202mA
-458mV    269.3uA    472.4uA    476.3uA
-254mV    28.45uA    20.72uA    43.74uA
2.5V      0A         0A         0A
[Ramp]
| variable   typ   min   max
dV/dt_r   0.978/0.233n   0.769/0.346n   1.224/0.127n
dV/dt_f   1.051/0.219n   0.800/0.328n   1.262/0.136n
R_load = 50.000
[Rising Waveform]
R_fixture= 50.000
V_fixture= 0.0
V_fixture_min= 0.0
V_fixture_max= 0.0
|time   V(typ)   V(min)   V(max)
0s        990.6uV    778.5uV    1.315mV
595ps     1.033mV    774.1uV    -30.44mV
795ps     682.6uV    774.1uV    1.716V
1.052ns   -20.37mV   914.9uV    1.97V
1.263ns   1.044V     673.5uV    2.007V
1.727ns   1.552V     -20.17mV   2.034V
2.032ns   1.592V     810.9mV    2.039V
2.27ns    1.609V     1.089V     2.04V
3.176ns   1.628V     1.254V     2.042V
20ns      1.631V     1.283V     2.042V
[Rising Waveform]
R_fixture= 50.000
V_fixture= 2.500
V_fixture_min= 2.380
V_fixture_max= 2.630
|time   V(typ)   V(min)   V(max)
0s        748.9mV    1.046V     526.3mV
551ps     748.9mV    1.046V     542.7mV
719ps     749.6mV    1.046V     2.369V
919ps     760.9mV    1.046V     2.578V
1.028ns   1.236V     1.046V     2.596V
1.254ns   2.368V     1.047V     2.614V
1.485ns   2.458V     1.07V      2.622V
1.898ns   2.486V     2.222V     2.628V
2.269ns   2.494V     2.353V     2.629V
20ns      2.5V       2.38V      2.63V
[Falling Waveform]
R_fixture= 50.000
V_fixture= 2.500
V_fixture_min= 2.380
V_fixture_max= 2.630
|time   V(typ)   V(min)   V(max)
0s        2.5V       2.38V      2.63V
608ps     2.5V       2.38V      2.685V
832ps     2.501V     2.38V      811.3mV
1.102ns   2.522V     2.38V      573mV
1.225ns   1.771V     2.38V      555.1mV
1.585ns   857.2mV    2.379V     534.1mV
1.868ns   787.4mV    2.424V     529.2mV
2.389ns   759.3mV    1.239V     527mV
3.186ns   750.3mV    1.069V     526.3mV
20ns      748.8mV    1.046V     526.2mV
[Falling Waveform]
R_fixture= 50.000
V_fixture= 0.0
V_fixture_min= 0.0
V_fixture_max= 0.0
|time   V(typ)   V(min)   V(max)
0s        1.631V     1.283V     2.042V
584ps     1.631V     1.283V     2.03V
731ps     1.631V     1.283V     269.7mV
1.07ns    1.394V     1.283V     23.76mV
1.253ns   198.6mV    1.283V     12.62mV
1.639ns   21.14mV    1.288V     4.312mV
1.764ns   16.03mV    1.138V     3.286mV
2.057ns   7.677mV    171.8mV    2.068mV
2.419ns   3.596mV    23.33mV    1.521mV
20ns      990.4uV    778.4uV    1.315mV
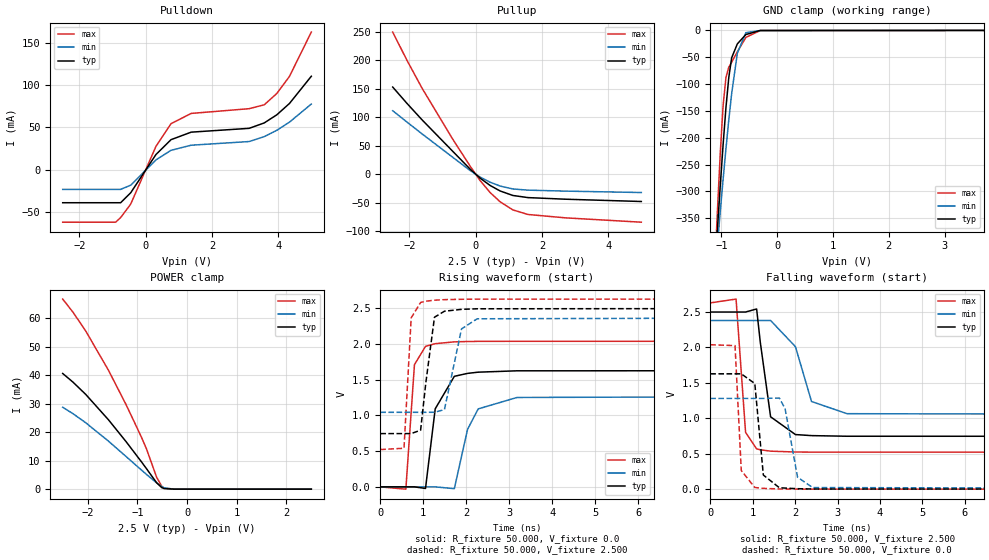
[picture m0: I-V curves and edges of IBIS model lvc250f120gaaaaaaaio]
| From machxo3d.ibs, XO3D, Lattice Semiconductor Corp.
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|   Model lvc250f120gaaaaaaaio
[Model] lvc250f120gaaaaaaaio
Model_type I/O
Polarity   Non-Inverting
Enable   Active-Low
Vinl =  0.700V
Vinh =  1.700V
Vmeas =  1.250V
Cref =  0.0F
Rref =  1.000M
Vref =  0.0V
C_comp   4.200pF   3.800pF   7.500pF
[Temperature Range]   25.000   0.105k   -40.000
[Voltage Range]   2.500V   2.380V   2.630V
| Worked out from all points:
|   slope of the pulldown table from 0 to 0.375 V, typ, clamps not added: 18.1 ohm
|   slope of the pullup table from 0 to 0.375 V, typ, clamps not added: 21.7 ohm
|   GND clamp passes 1 mA (typ) near -0.43 V on its own axis
|   POWER clamp passes 1 mA (typ) near -0.54 V on its own axis
|   rising waveform, R_fixture 50.000, V_fixture 0.0: 20-80 % time 234ps typ, 349ps min, 127ps max; typ from 0 V to 1.63 V
|   rising waveform, R_fixture 50.000, V_fixture 2.500: 20-80 % time 161ps typ, 259ps min, 87.7ps max; typ from 0.745 V to 2.5 V
|   falling waveform, R_fixture 50.000, V_fixture 2.500: 20-80 % time 217ps typ, 326ps min, 135ps max; typ from 2.5 V to 0.745 V
|   falling waveform, R_fixture 50.000, V_fixture 0.0: 20-80 % time 131ps typ, 212ps min, 80.7ps max; typ from 1.63 V to 0 V
[Pulldown]
|Voltage   I(typ)   I(min)   I(max)
-2.5V     -39.23mA   -23.44mA   -62.24mA
-904mV    -39.23mA   -23.44mA   -62.24mA
-752mV    -39.23mA   -23.44mA   -56.76mA
-448mV    -27.42mA   -18.49mA   -40.8mA
312mV     17.71mA    11.41mA    27.31mA
768mV     35.33mA    22.74mA    54.24mA
1.376V    44.21mA    28.76mA    66.35mA
3.124V    48.71mA    33.11mA    71.94mA
3.58V     55.12mA    38.9mA     76.53mA
3.96V     64.74mA    46.41mA    89.96mA
4.34V     78.07mA    56.04mA    110.1mA
5V        110.3mA    77.42mA    162.5mA
[Pullup]
|Voltage   I(typ)   I(min)   I(max)
-2.5V     153.1mA    111.5mA    249.6mA
-2.068V   124.3mA    91.56mA    199.8mA
-1.612V   95.34mA    70.73mA    150.8mA
-700mV    40.91mA    30.25mA    62.53mA
-168mV    9.171mA    6.69mA     14.58mA
136mV     -6.852mA   -4.921mA   -11.06mA
440mV     -19.77mA   -14.08mA   -32.21mA
744mV     -29.47mA   -20.78mA   -48.57mA
1.124V    -37.28mA   -25.86mA   -62.59mA
1.58V     -41.03mA   -27.92mA   -70.68mA
2.72V     -43.87mA   -29.66mA   -76.62mA
5V        -47.88mA   -32.11mA   -84.21mA
[GND_clamp]
|Voltage   I(typ)   I(min)   I(max)
-2.5V     -2.99A     -2.35A     -4.091A
-1.123V   -455.1mA   -463.2mA   -453.7mA
-1.072V   -370.5mA   -399.5mA   -336.3mA
-1.021V   -289.2mA   -337.4mA   -228.6mA
-970mV    -212.6mA   -277.4mA   -140mA
-919mV    -143.6mA   -220.1mA   -87.4mA
-868mV    -87.39mA   -166.5mA   -68.45mA
-817mV    -50.94mA   -117.8mA   -59.13mA
-715mV    -24.99mA   -42.37mA   -39.7mA
-562mV    -7.608mA   -4.125mA   -12.95mA
-307mV    -97.66uA   -51.76uA   -173.8uA
5V        114uA      49.35uA    266.8uA
[POWER_clamp]
|Voltage   I(typ)   I(min)   I(max)
-2.5V     40.55mA    28.7mA     66.64mA
-2.294V   37.53mA    26.47mA    62.05mA
-2.039V   33.25mA    23.31mA    55.5mA
-1.58V    24.33mA    16.84mA    41.69mA
-1.223V   16.6mA     11.41mA    29.54mA
-917mV    9.596mA    6.709mA    18.24mA
-815mV    7.18mA     5.166mA    14.11mA
-611mV    2.243mA    2.205mA    4.167mA
-509mV    558uA      921.7uA    1.059mA
-458mV    208uA      438.7uA    350.8uA
-254mV    2.162uA    3.635uA    1.029uA
2.5V      0A         0A         0A
[Ramp]
| variable   typ   min   max
dV/dt_r   0.976/0.234n   0.768/0.347n   1.223/0.127n
dV/dt_f   1.052/0.218n   0.802/0.327n   1.263/0.135n
R_load = 50.000
[Rising Waveform]
R_fixture= 50.000
V_fixture= 0.0
V_fixture_min= 0.0
V_fixture_max= 0.0
|time   V(typ)   V(min)   V(max)
0s        4.486nV    34.65nV    14.98nV
595ps     43.37uV    -3.403uV   -32.25mV
795ps     -305uV     -3.403uV   1.71V
1.052ns   -22.13mV   21.4uV     1.966V
1.278ns   1.092V     -132.6uV   2.004V
1.723ns   1.547V     -25.33mV   2.029V
2.03ns    1.588V     804.3mV    2.034V
2.278ns   1.605V     1.091V     2.036V
3.181ns   1.624V     1.251V     2.037V
20ns      1.627V     1.28V      2.038V
[Rising Waveform]
R_fixture= 50.000
V_fixture= 2.500
V_fixture_min= 2.380
V_fixture_max= 2.630
|time   V(typ)   V(min)   V(max)
0s        745.3mV    1.043V     522.1mV
552ps     745.3mV    1.043V     540.2mV
719ps     746mV      1.043V     2.365V
938ps     792.7mV    1.043V     2.58V
1.061ns   1.463V     1.043V     2.598V
1.261ns   2.374V     1.044V     2.612V
1.493ns   2.458V     1.081V     2.62V
1.89ns    2.484V     2.21V      2.625V
2.254ns   2.492V     2.352V     2.627V
20ns      2.499V     2.379V     2.628V
[Falling Waveform]
R_fixture= 50.000
V_fixture= 2.500
V_fixture_min= 2.380
V_fixture_max= 2.630
|time   V(typ)   V(min)   V(max)
0s        2.499V     2.379V     2.628V
608ps     2.499V     2.379V     2.682V
832ps     2.499V     2.379V     802.1mV
1.093ns   2.542V     2.379V     568.6mV
1.179ns   2.074V     2.379V     555.6mV
1.422ns   1.021V     2.38V      536.2mV
2.008ns   770.4mV    2.01V      524.2mV
2.387ns   755.5mV    1.237V     522.6mV
3.224ns   746.6mV    1.065V     522.1mV
20ns      745.3mV    1.043V     522.1mV
[Falling Waveform]
R_fixture= 50.000
V_fixture= 0.0
V_fixture_min= 0.0
V_fixture_max= 0.0
|time   V(typ)   V(min)   V(max)
0s        1.627V     1.28V      2.038V
584ps     1.627V     1.28V      2.025V
731ps     1.627V     1.28V      263.5mV
1.05ns    1.49V      1.28V      23.71mV
1.251ns   199.4mV    1.28V      11.29mV
1.628ns   20.47mV    1.286V     2.947mV
1.764ns   15.39mV    1.135V     1.939mV
2.058ns   6.6mV      168mV      730.9uV
2.413ns   2.532mV    22.75mV    294.7uV
20ns      43.56nV    83.03nV    -176.6nV
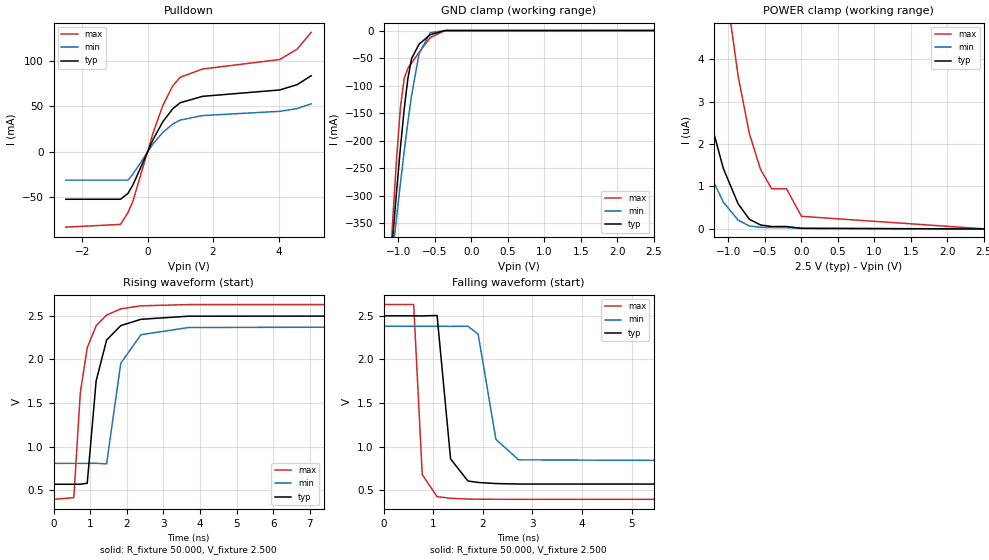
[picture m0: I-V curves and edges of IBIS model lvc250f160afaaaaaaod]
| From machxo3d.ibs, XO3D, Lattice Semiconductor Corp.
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|   Model lvc250f160afaaaaaaod
[Model] lvc250f160afaaaaaaod
Model_type I/O_open_drain
Polarity   Non-Inverting
Enable   Active-Low
Vinl =  0.700V
Vinh =  1.700V
Vmeas =  1.250V
Cref =  0.0F
Rref = 10.00k
Vref = 2.50V
C_comp   4.200pF   3.800pF   7.500pF
[Temperature Range]   25.000   0.105k   -40.000
[Voltage Range]   2.500V   2.380V   2.630V
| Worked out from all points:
|   slope of the pulldown table from 0 to 0.375 V, typ, clamps not added: 13.6 ohm
|   GND clamp passes 1 mA (typ) near -0.43 V on its own axis
|   rising waveform, R_fixture 50.000, V_fixture 2.500: 20-80 % time 331ps typ, 335ps min, 338ps max; typ from 0.567 V to 2.5 V
|   falling waveform, R_fixture 50.000, V_fixture 2.500: 20-80 % time 167ps typ, 278ps min, 102ps max; typ from 2.5 V to 0.567 V
[Pulldown]
|Voltage   I(typ)   I(min)   I(max)
-2.5V     -52.31mA   -31.26mA   -82.98mA
-828mV    -52.31mA   -31.26mA   -79.94mA
-600mV    -45.86mA   -31.26mA   -66.93mA
-448mV    -36.56mA   -24.66mA   -54.4mA
160mV     12.89mA    8.306mA    19.88mA
464mV     32.88mA    21.18mA    50.69mA
768mV     47.11mA    30.32mA    72.33mA
996mV     53.81mA    34.73mA    81.8mA
1.68V     60.84mA    39.71mA    90.86mA
4.036V    67.83mA    44.35mA    101.3mA
4.568V    73.67mA    47.37mA    112.7mA
5V        83.54mA    52.56mA    131.2mA
[GND_clamp]
|Voltage   I(typ)   I(min)   I(max)
-2.5V     -2.99A     -2.35A     -4.091A
-1.123V   -455.1mA   -463.2mA   -453.6mA
-1.072V   -370.5mA   -399.5mA   -336.3mA
-1.021V   -289.1mA   -337.4mA   -228.5mA
-970mV    -212.6mA   -277.3mA   -139.9mA
-919mV    -143.6mA   -220.1mA   -87.34mA
-868mV    -87.35mA   -166.5mA   -68.39mA
-817mV    -50.9mA    -117.8mA   -59.07mA
-715mV    -24.94mA   -42.34mA   -39.63mA
-562mV    -7.547mA   -4.077mA   -12.85mA
-358mV    -114uA     -53.77uA   -172.8uA
2.5V      0A         0A         0A
[POWER_clamp]
|Voltage   I(typ)   I(min)   I(max)
-2.5V     16.57uA    10.06uA    44.17uA
-2.09V    10.8uA     6.285uA    30.12uA
-1.682V   6.109uA    3.358uA    18.45uA
-1.376V   3.384uA    1.736uA    11.44uA
-1.07V    1.428uA    632.8nA    6.128uA
-866mV    590.7nA    207.8nA    3.594uA
-713mV    230.3nA    70.46nA    2.252uA
-560mV    93.26nA    38.97nA    1.406uA
-407mV    57.69nA    33.36nA    946.1nA
-203mV    57.69nA    32.35nA    946.1nA
1mV       16.06nA    10.58nA    297.5nA
2.5V      0A         0A         3.667nA
[Ramp]
| variable   typ   min   max
dV/dt_r   1.160/0.333n   0.944/0.335n   1.341/0.337n
dV/dt_f   1.160/0.168n   0.944/0.275n   1.341/0.101n
R_load = 50.000
[Rising Waveform]
R_fixture= 50.000
V_fixture= 2.500
V_fixture_min= 2.380
V_fixture_max= 2.630
|time   V(typ)   V(min)   V(max)
0s        567.4mV    806.9mV    394.6mV
554ps     567.4mV    806.9mV    413.4mV
732ps     568mV      806.9mV    1.621V
921ps     579mV      806.9mV    2.134V
1.164ns   1.752V     807.9mV    2.386V
1.45ns    2.222V     802.2mV    2.509V
1.838ns   2.388V     1.957V     2.58V
2.388ns   2.46V      2.283V     2.615V
3.688ns   2.496V     2.366V     2.629V
20ns      2.5V       2.38V      2.63V
[Falling Waveform]
R_fixture= 50.000
V_fixture= 2.500
V_fixture_min= 2.380
V_fixture_max= 2.630
|time   V(typ)   V(min)   V(max)
0s        2.5V       2.38V      2.63V
605ps     2.5V       2.38V      2.63V
778ps     2.499V     2.38V      677.2mV
1.077ns   2.504V     2.38V      425.1mV
1.349ns   858.4mV    2.379V     406.8mV
1.699ns   604.7mV    2.38V      397.8mV
1.905ns   588.3mV    2.29V      396.1mV
2.263ns   575.6mV    1.082V     395mV
2.721ns   570.3mV    847.8mV    394.7mV
20ns      567.3mV    806.9mV    394.6mV
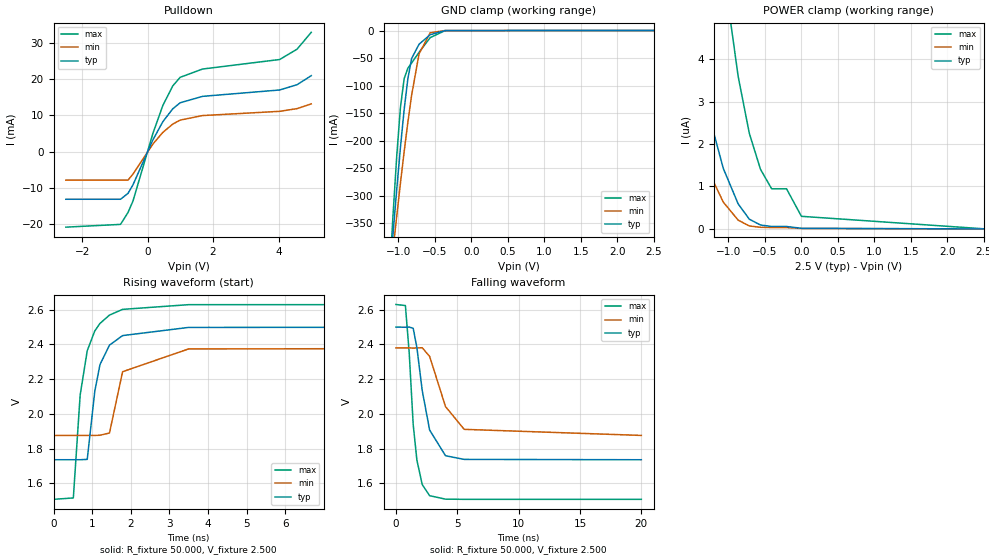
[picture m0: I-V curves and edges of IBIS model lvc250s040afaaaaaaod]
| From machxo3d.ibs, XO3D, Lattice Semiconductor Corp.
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|   Model lvc250s040afaaaaaaod
[Model] lvc250s040afaaaaaaod
Model_type I/O_open_drain
Polarity   Non-Inverting
Enable   Active-Low
Vinl =  0.700V
Vinh =  1.700V
Vmeas =  1.250V
Cref =  0.0F
Rref = 10.00k
Vref = 2.50V
C_comp   4.200pF   3.800pF   7.500pF
[Temperature Range]   25.000   0.105k   -40.000
[Voltage Range]   2.500V   2.380V   2.630V
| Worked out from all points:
|   slope of the pulldown table from 0 to 0.375 V, typ, clamps not added: 54.4 ohm
|   GND clamp passes 1 mA (typ) near -0.43 V on its own axis
|   rising waveform, R_fixture 50.000, V_fixture 2.500: 20-80 % time 344ps typ, 349ps min, 345ps max; typ from 1.74 V to 2.5 V
|   falling waveform, R_fixture 50.000, V_fixture 2.500: 20-80 % time 1.07ns typ, 1.56ns min, 705ps max; typ from 2.5 V to 1.74 V
[Pulldown]
|Voltage   I(typ)   I(min)   I(max)
-2.5V     -13.08mA   -7.815mA   -20.75mA
-828mV    -13.08mA   -7.815mA   -19.99mA
-600mV    -11.47mA   -7.815mA   -16.73mA
-448mV    -9.14mA    -6.165mA   -13.6mA
160mV     3.222mA    2.076mA    4.97mA
464mV     8.221mA    5.294mA    12.67mA
768mV     11.78mA    7.58mA     18.08mA
996mV     13.45mA    8.684mA    20.45mA
1.68V     15.21mA    9.928mA    22.72mA
4.036V    16.96mA    11.09mA    25.34mA
4.568V    18.42mA    11.84mA    28.18mA
5V        20.89mA    13.14mA    32.81mA
[GND_clamp]
|Voltage   I(typ)   I(min)   I(max)
-2.5V     -2.99A     -2.35A     -4.091A
-1.123V   -455.1mA   -463.2mA   -453.6mA
-1.072V   -370.5mA   -399.5mA   -336.3mA
-1.021V   -289.1mA   -337.4mA   -228.5mA
-970mV    -212.6mA   -277.3mA   -139.9mA
-919mV    -143.6mA   -220.1mA   -87.34mA
-868mV    -87.35mA   -166.5mA   -68.39mA
-817mV    -50.9mA    -117.8mA   -59.07mA
-715mV    -24.94mA   -42.34mA   -39.63mA
-562mV    -7.547mA   -4.077mA   -12.85mA
-358mV    -114uA     -53.77uA   -172.8uA
2.5V      0A         0A         0A
[POWER_clamp]
|Voltage   I(typ)   I(min)   I(max)
-2.5V     16.57uA    10.06uA    44.17uA
-2.09V    10.8uA     6.285uA    30.12uA
-1.682V   6.109uA    3.358uA    18.45uA
-1.376V   3.384uA    1.736uA    11.44uA
-1.07V    1.428uA    632.9nA    6.128uA
-866mV    590.6nA    207.8nA    3.594uA
-713mV    230.3nA    70.5nA     2.252uA
-560mV    93.24nA    39.01nA    1.406uA
-407mV    57.67nA    33.39nA    946nA
-203mV    57.67nA    32.38nA    946nA
1mV       16.06nA    10.58nA    297.5nA
2.5V      0A         0A         3.667nA
[Ramp]
| variable   typ   min   max
dV/dt_r   0.459/0.344n   0.303/0.349n   0.673/0.345n
dV/dt_f   0.459/1.058n   0.303/1.589n   0.673/0.703n
R_load = 50.000
[Rising Waveform]
R_fixture= 50.000
V_fixture= 2.500
V_fixture_min= 2.380
V_fixture_max= 2.630
|time   V(typ)   V(min)   V(max)
0s        1.736V     1.876V     1.508V
513ps     1.736V     1.876V     1.516V
690ps     1.736V     1.876V     2.109V
873ps     1.738V     1.876V     2.364V
1.069ns   2.131V     1.876V     2.478V
1.203ns   2.284V     1.877V     2.521V
1.449ns   2.396V     1.89V      2.569V
1.789ns   2.451V     2.243V     2.602V
3.496ns   2.498V     2.374V     2.629V
20ns      2.5V       2.38V      2.63V
[Falling Waveform]
R_fixture= 50.000
V_fixture= 2.500
V_fixture_min= 2.380
V_fixture_max= 2.630
|time   V(typ)   V(min)   V(max)
0s        2.5V       2.38V      2.63V
772ps     2.499V     2.38V      2.624V
1.085ns   2.5V       2.38V      2.349V
1.408ns   2.493V     2.379V     1.938V
1.709ns   2.382V     2.38V      1.734V
2.143ns   2.135V     2.381V     1.593V
2.747ns   1.907V     2.331V     1.529V
4.042ns   1.759V     2.042V     1.509V
5.564ns   1.738V     1.911V     1.508V
20ns      1.736V     1.876V     1.508V
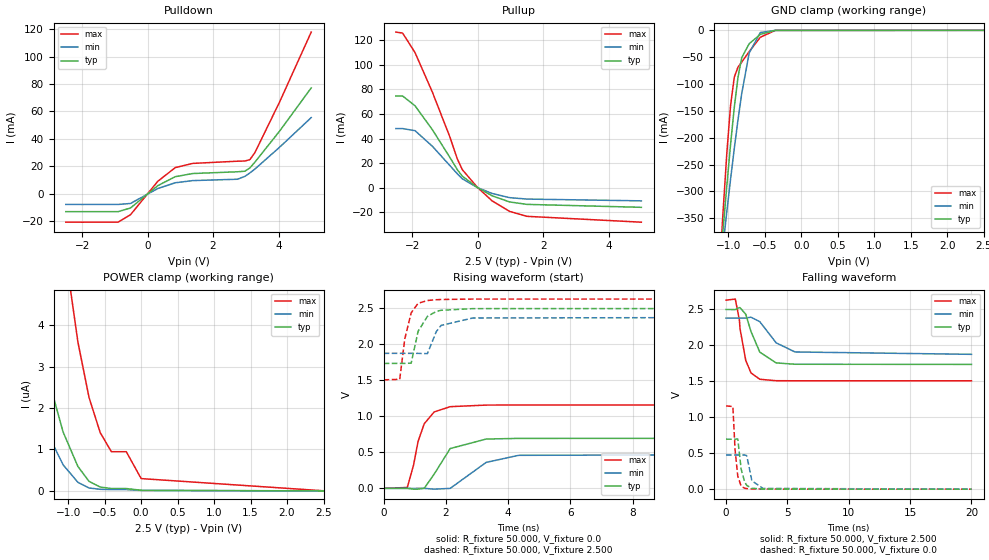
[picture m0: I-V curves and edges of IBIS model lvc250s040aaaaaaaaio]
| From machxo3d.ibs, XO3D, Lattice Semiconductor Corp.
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|   Model lvc250s040aaaaaaaaio
[Model] lvc250s040aaaaaaaaio
Model_type I/O
Polarity   Non-Inverting
Enable   Active-Low
Vinl =  0.700V
Vinh =  1.700V
Vmeas =  1.250V
Cref =  0.0F
Rref =  1.000M
Vref =  0.0V
C_comp   4.200pF   3.800pF   7.500pF
[Temperature Range]   25.000   0.105k   -40.000
[Voltage Range]   2.500V   2.380V   2.630V
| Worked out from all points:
|   slope of the pulldown table from 0 to 0.375 V, typ, clamps not added: 54.4 ohm
|   slope of the pullup table from 0 to 0.375 V, typ, clamps not added: 65.1 ohm
|   GND clamp passes 1 mA (typ) near -0.43 V on its own axis
|   rising waveform, R_fixture 50.000, V_fixture 0.0: 20-80 % time 604ps typ, 886ps min, 438ps max; typ from 0 V to 0.696 V
|   rising waveform, R_fixture 50.000, V_fixture 2.500: 20-80 % time 349ps typ, 361ps min, 276ps max; typ from 1.74 V to 2.5 V
|   falling waveform, R_fixture 50.000, V_fixture 2.500: 20-80 % time 1.06ns typ, 1.58ns min, 705ps max; typ from 2.5 V to 1.74 V
|   falling waveform, R_fixture 50.000, V_fixture 0.0: 20-80 % time 358ps typ, 394ps min, 296ps max; typ from 0.696 V to 0 V
[Pulldown]
|Voltage   I(typ)   I(min)   I(max)
-2.5V     -13.08mA   -7.815mA   -20.75mA
-904mV    -13.08mA   -7.815mA   -20.75mA
-524mV    -10.41mA   -7.109mA   -15.34mA
312mV     5.902mA    3.803mA    9.102mA
844mV     12.43mA    8.006mA    19.04mA
1.376V    14.74mA    9.586mA    22.12mA
2.744V    16.02mA    10.58mA    23.73mA
2.972V    16.43mA    12.65mA    23.88mA
3.124V    18.81mA    15.15mA    24.86mA
3.276V    22.96mA    17.94mA    29.87mA
4.036V    45.76mA    33.99mA    67.06mA
5V        77.21mA    55.54mA    117.9mA
[Pullup]
|Voltage   I(typ)   I(min)   I(max)
-2.5V     74.67mA    48.16mA    126.7mA
-2.296V   74.67mA    48.16mA    125.9mA
-1.916V   66.7mA     46.45mA    110mA
-1.384V   47.15mA    33.7mA     77.68mA
-852mV    24.7mA     18.03mA    41.35mA
-624mV    14.72mA    11.36mA    23.44mA
-472mV    9.401mA    7.281mA    14.74mA
-16mV     282.9uA    204.1uA    454.4uA
440mV     -6.588mA   -4.693mA   -10.74mA
972mV     -11.57mA   -8.084mA   -19.27mA
1.504V    -13.57mA   -9.251mA   -23.3mA
5V        -15.96mA   -10.7mA    -28.07mA
[GND_clamp]
|Voltage   I(typ)   I(min)   I(max)
-2.5V     -2.99A     -2.35A     -4.091A
-1.123V   -455.1mA   -463.2mA   -453.6mA
-1.072V   -370.5mA   -399.5mA   -336.3mA
-1.021V   -289.1mA   -337.4mA   -228.5mA
-970mV    -212.6mA   -277.3mA   -139.9mA
-919mV    -143.6mA   -220.1mA   -87.34mA
-868mV    -87.35mA   -166.5mA   -68.39mA
-817mV    -50.9mA    -117.8mA   -59.07mA
-715mV    -24.94mA   -42.34mA   -39.63mA
-562mV    -7.547mA   -4.077mA   -12.85mA
-358mV    -114uA     -53.77uA   -172.8uA
2.5V      0A         0A         0A
[POWER_clamp]
|Voltage   I(typ)   I(min)   I(max)
-2.5V     16.57uA    10.06uA    44.17uA
-2.09V    10.8uA     6.285uA    30.12uA
-1.682V   6.109uA    3.358uA    18.45uA
-1.376V   3.384uA    1.736uA    11.44uA
-1.07V    1.428uA    632.9nA    6.128uA
-866mV    590.6nA    207.8nA    3.594uA
-713mV    230.3nA    70.5nA     2.252uA
-560mV    93.25nA    39.01nA    1.406uA
-407mV    57.68nA    33.4nA     946.1nA
-203mV    57.68nA    32.39nA    946.1nA
1mV       16.06nA    10.58nA    297.5nA
2.5V      0A         0A         3.667nA
[Ramp]
| variable   typ   min   max
dV/dt_r   0.417/0.606n   0.285/0.862n   0.695/0.439n
dV/dt_f   0.459/1.070n   0.303/1.589n   0.673/0.702n
R_load = 50.000
[Rising Waveform]
R_fixture= 50.000
V_fixture= 0.0
V_fixture_min= 0.0
V_fixture_max= 0.0
|time   V(typ)   V(min)   V(max)
0s        9.431nV    63.61nV    34.88nV
759ps     351.8uV    3.004uV    12.47mV
960ps     -10.83mV   27.02uV    321.5mV
1.106ns   -10.33mV   237.7uV    653.1mV
1.304ns   1.646mV    -77.49uV   897.9mV
1.624ns   198.3mV    -11.2mV    1.062V
2.137ns   553mV      -333.7uV   1.135V
3.294ns   685.2mV    360.9mV    1.157V
4.337ns   694.3mV    459mV      1.158V
20ns      695.7mV    475.1mV    1.159V
[Rising Waveform]
R_fixture= 50.000
V_fixture= 2.500
V_fixture_min= 2.380
V_fixture_max= 2.630
|time   V(typ)   V(min)   V(max)
0s        1.736V     1.876V     1.508V
516ps     1.736V     1.876V     1.515V
679ps     1.736V     1.876V     2.076V
884ps     1.74V      1.876V     2.439V
1.107ns   2.182V     1.876V     2.571V
1.405ns   2.389V     1.871V     2.61V
1.691ns   2.458V     2.177V     2.621V
1.845ns   2.474V     2.264V     2.624V
2.862ns   2.497V     2.367V     2.63V
20ns      2.5V       2.38V      2.63V
[Falling Waveform]
R_fixture= 50.000
V_fixture= 2.500
V_fixture_min= 2.380
V_fixture_max= 2.630
|time   V(typ)   V(min)   V(max)
0s        2.5V       2.38V      2.63V
752ps     2.499V     2.38V      2.645V
1.083ns   2.526V     2.38V      2.36V
1.138ns   2.526V     2.38V      2.235V
1.607ns   2.433V     2.38V      1.791V
2.033ns   2.193V     2.393V     1.617V
2.753ns   1.906V     2.33V      1.529V
4.077ns   1.757V     2.037V     1.509V
5.616ns   1.738V     1.909V     1.508V
20ns      1.736V     1.876V     1.508V
[Falling Waveform]
R_fixture= 50.000
V_fixture= 0.0
V_fixture_min= 0.0
V_fixture_max= 0.0
|time   V(typ)   V(min)   V(max)
0s        695.7mV    475.1mV    1.159V
556ps     695.7mV    475mV      1.15V
735ps     695.4mV    475.1mV    548.1mV
956ps     698.2mV    475.1mV    181.8mV
1.232ns   278.5mV    474.9mV    39.84mV
1.515ns   102mV      475.4mV    12.84mV
1.687ns   52.32mV    466.2mV    7.526mV
2.106ns   12.59mV    115.6mV    1.778mV
3.02ns    1.442mV    10.39mV    169.7uV
20ns      17.25nV    115.2nV    35.04nV
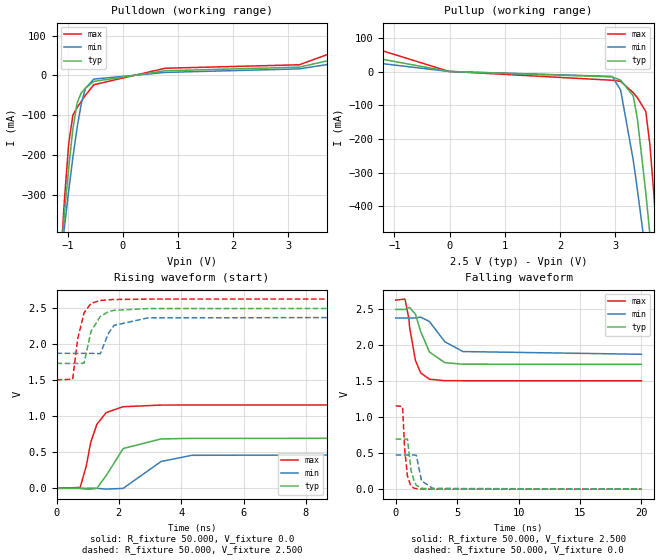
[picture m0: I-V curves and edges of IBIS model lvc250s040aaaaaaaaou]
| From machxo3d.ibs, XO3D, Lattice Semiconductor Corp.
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|   Model lvc250s040aaaaaaaaou
[Model] lvc250s040aaaaaaaaou
Model_type Output
Polarity   Non-Inverting
Enable   Active-High
Vmeas =  1.250V
Cref =  0.0F
Rref =  1.000M
Vref =  0.0V
C_comp   4.200pF   3.800pF   7.500pF
[Temperature Range]   25.000   0.105k   -40.000
[Voltage Range]   2.500V   2.380V   2.630V
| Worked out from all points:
|   slope of the pulldown table from 0 to 0.375 V, typ, clamps not added: 54.4 ohm
|   slope of the pullup table from 0 to 0.375 V, typ, clamps not added: 65.1 ohm
|   rising waveform, R_fixture 50.000, V_fixture 0.0: 20-80 % time 603ps typ, 867ps min, 438ps max; typ from 0 V to 0.696 V
|   rising waveform, R_fixture 50.000, V_fixture 2.500: 20-80 % time 350ps typ, 362ps min, 276ps max; typ from 1.74 V to 2.5 V
|   falling waveform, R_fixture 50.000, V_fixture 2.500: 20-80 % time 1.06ns typ, 1.56ns min, 707ps max; typ from 2.5 V to 1.74 V
|   falling waveform, R_fixture 50.000, V_fixture 0.0: 20-80 % time 355ps typ, 392ps min, 297ps max; typ from 0.696 V to 0 V
[Pulldown]
|Voltage   I(typ)   I(min)   I(max)
-2.5V     -2.991A    -2.35A     -4.091A
-1.132V   -472.6mA   -475.7mA   -480.1mA
-1.056V   -348.1mA   -381.3mA   -311.4mA
-980mV    -233mA     -290.9mA   -172.6mA
-904mV    -135.4mA   -206.7mA   -100.2mA
-828mV    -69.7mA    -132mA     -80.94mA
-752mV    -44.04mA   -71.78mA   -65.89mA
-676mV    -32.05mA   -32.21mA   -49.93mA
-524mV    -15.09mA   -9.266mA   -23.38mA
768mV     11.78mA    7.58mA     18.08mA
3.2V      20.83mA    16.52mA    26.8mA
5V        77.23mA    55.55mA    117.9mA
[Pullup]
|Voltage   I(typ)   I(min)   I(max)
-2.5V     74.68mA    48.17mA    126.8mA
-16mV     282.9uA    204.1uA    454.8uA
2.948V    -15.97mA   -14.48mA   -25.89mA
3.1V      -25.95mA   -55.2mA    -29.21mA
3.328V    -71.89mA   -262.4mA   -62.59mA
3.404V    -140.5mA   -351.2mA   -77.65mA
3.556V    -359.8mA   -541mA     -118.6mA
3.632V    -485.6mA   -639.6mA   -219.2mA
3.708V    -616.1mA   -739.9mA   -376.5mA
3.784V    -749.7mA   -841.4mA   -554.7mA
3.86V     -885.5mA   -943.8mA   -742.2mA
5V        -3.006A    -2.53A     -3.767A
[Ramp]
| variable   typ   min   max
dV/dt_r   0.417/0.606n   0.285/0.862n   0.695/0.439n
dV/dt_f   0.459/1.067n   0.303/1.589n   0.673/0.702n
R_load = 50.000
[Rising Waveform]
R_fixture= 50.000
V_fixture= 0.0
V_fixture_min= 0.0
V_fixture_max= 0.0
|time   V(typ)   V(min)   V(max)
0s        9.431nV    63.61nV    34.88nV
759ps     315.5uV    -970.9nV   12.47mV
960ps     -11.47mV   23.38uV    321.5mV
1.094ns   -10.79mV   230.8uV    632.6mV
1.292ns   -759uV     189.9uV    887.4mV
1.594ns   177.4mV    -10.9mV    1.053V
2.137ns   553mV      -544.2uV   1.134V
3.354ns   686.5mV    373.1mV    1.157V
4.337ns   694.3mV    459mV      1.158V
20ns      695.7mV    475.1mV    1.159V
[Rising Waveform]
R_fixture= 50.000
V_fixture= 2.500
V_fixture_min= 2.380
V_fixture_max= 2.630
|time   V(typ)   V(min)   V(max)
0s        1.736V     1.876V     1.508V
516ps     1.736V     1.876V     1.515V
679ps     1.736V     1.876V     2.076V
884ps     1.74V      1.876V     2.439V
1.107ns   2.182V     1.876V     2.571V
1.405ns   2.389V     1.871V     2.61V
1.667ns   2.454V     2.155V     2.62V
1.845ns   2.473V     2.264V     2.624V
2.931ns   2.498V     2.369V     2.63V
20ns      2.5V       2.38V      2.63V
[Falling Waveform]
R_fixture= 50.000
V_fixture= 2.500
V_fixture_min= 2.380
V_fixture_max= 2.630
|time   V(typ)   V(min)   V(max)
0s        2.5V       2.38V      2.63V
755ps     2.499V     2.38V      2.644V
1.083ns   2.527V     2.38V      2.36V
1.129ns   2.527V     2.38V      2.256V
1.607ns   2.433V     2.38V      1.791V
2.033ns   2.193V     2.393V     1.617V
2.75ns    1.907V     2.331V     1.529V
3.996ns   1.76V      2.05V      1.509V
5.479ns   1.738V     1.914V     1.508V
20ns      1.736V     1.876V     1.508V
[Falling Waveform]
R_fixture= 50.000
V_fixture= 0.0
V_fixture_min= 0.0
V_fixture_max= 0.0
|time   V(typ)   V(min)   V(max)
0s        695.7mV    475.1mV    1.159V
556ps     695.7mV    475mV      1.15V
733ps     695.4mV    475mV      552.4mV
956ps     698.2mV    475.2mV    182.5mV
1.247ns   263.3mV    474.9mV    37.52mV
1.509ns   104.3mV    475.4mV    13.16mV
1.679ns   53.98mV    469.5mV    7.746mV
2.106ns   12.61mV    115.6mV    1.912mV
3.022ns   1.443mV    10.36mV    206.6uV
20ns      17.25nV    115.2nV    35.02nV
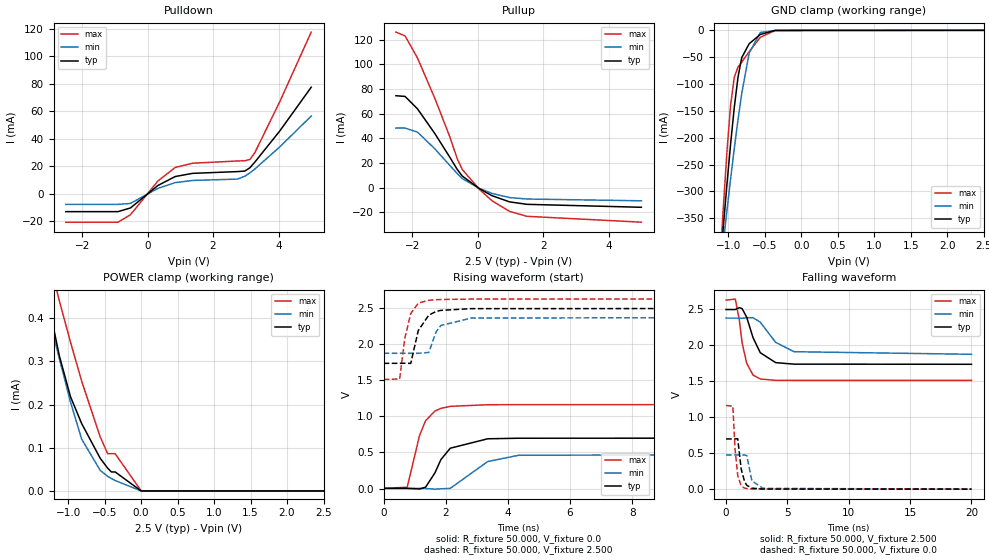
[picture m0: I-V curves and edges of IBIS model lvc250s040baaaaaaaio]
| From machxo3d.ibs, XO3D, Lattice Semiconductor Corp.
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|   Model lvc250s040baaaaaaaio
[Model] lvc250s040baaaaaaaio
Model_type I/O
Polarity   Non-Inverting
Enable   Active-Low
Vinl =  0.700V
Vinh =  1.700V
Vmeas =  1.250V
Cref =  0.0F
Rref =  1.000M
Vref =  0.0V
C_comp   4.200pF   3.800pF   7.500pF
[Temperature Range]   25.000   0.105k   -40.000
[Voltage Range]   2.500V   2.380V   2.630V
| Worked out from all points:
|   slope of the pulldown table from 0 to 0.375 V, typ, clamps not added: 54.4 ohm
|   slope of the pullup table from 0 to 0.375 V, typ, clamps not added: 65.1 ohm
|   GND clamp passes 1 mA (typ) near -0.43 V on its own axis
|   POWER clamp passes 1 mA (typ) near -1.90 V on its own axis
|   rising waveform, R_fixture 50.000, V_fixture 0.0: 20-80 % time 605ps typ, 868ps min, 437ps max; typ from 0.002 V to 0.7 V
|   rising waveform, R_fixture 50.000, V_fixture 2.500: 20-80 % time 350ps typ, 361ps min, 275ps max; typ from 1.74 V to 2.5 V
|   falling waveform, R_fixture 50.000, V_fixture 2.500: 20-80 % time 1.05ns typ, 1.59ns min, 702ps max; typ from 2.5 V to 1.74 V
|   falling waveform, R_fixture 50.000, V_fixture 0.0: 20-80 % time 360ps typ, 396ps min, 299ps max; typ from 0.7 V to 0.002 V
[Pulldown]
|Voltage   I(typ)   I(min)   I(max)
-2.5V     -13.08mA   -7.815mA   -20.75mA
-904mV    -13.08mA   -7.815mA   -20.75mA
-524mV    -10.41mA   -7.109mA   -15.34mA
312mV     5.902mA    3.803mA    9.102mA
844mV     12.43mA    8.006mA    19.04mA
1.376V    14.74mA    9.586mA    22.12mA
2.744V    16.02mA    10.57mA    23.73mA
2.972V    16.42mA    12.64mA    23.88mA
3.124V    18.76mA    15.12mA    24.81mA
3.276V    22.89mA    17.87mA    29.77mA
4.036V    45.44mA    33.92mA    66.69mA
5V        77.33mA    56.37mA    117.4mA
[Pullup]
|Voltage   I(typ)   I(min)   I(max)
-2.5V     74.64mA    48.35mA    126.3mA
-2.22V    74.04mA    48.35mA    123.2mA
-1.84V    63.93mA    45.06mA    105.2mA
-1.308V   43.79mA    31.42mA    72.33mA
-852mV    24.62mA    17.98mA    41.17mA
-624mV    14.67mA    11.34mA    23.35mA
-472mV    9.383mA    7.274mA    14.7mA
60mV      -1.036mA   -745uA     -1.668mA
440mV     -6.588mA   -4.693mA   -10.74mA
972mV     -11.57mA   -8.084mA   -19.27mA
1.504V    -13.57mA   -9.251mA   -23.3mA
5V        -15.96mA   -10.7mA    -28.07mA
[GND_clamp]
|Voltage   I(typ)   I(min)   I(max)
-2.5V     -2.99A     -2.35A     -4.091A
-1.123V   -455.1mA   -463.2mA   -453.7mA
-1.072V   -370.5mA   -399.5mA   -336.3mA
-1.021V   -289.2mA   -337.4mA   -228.6mA
-970mV    -212.6mA   -277.4mA   -140mA
-919mV    -143.6mA   -220.1mA   -87.39mA
-868mV    -87.38mA   -166.5mA   -68.44mA
-817mV    -50.93mA   -117.8mA   -59.12mA
-715mV    -24.98mA   -42.36mA   -39.69mA
-562mV    -7.596mA   -4.111mA   -12.93mA
-358mV    -193.4uA   -101.2uA   -309.3uA
2.5V      13.17nA    0A         -19.29uA
[POWER_clamp]
|Voltage   I(typ)   I(min)   I(max)
-2.5V     1.538mA    1.365mA    2.125mA
-1.325V   482.6uA    450.2uA    591.5uA
-1.274V   438.4uA    413.8uA    546.6uA
-1.121V   313.5uA    307.1uA    441uA
-968mV    218.6uA    206.5uA    345.2uA
-815mV    156.3uA    120.3uA    254.8uA
-560mV    75.6uA     47.55uA    125.2uA
-458mV    52.75uA    33.88uA    86.35uA
-407mV    44.01uA    28.68uA    86.35uA
-356mV    44.01uA    24.21uA    86.35uA
1mV       0A         0A         141nA
2.5V      0A         0A         0A
[Ramp]
| variable   typ   min   max
dV/dt_r   0.419/0.610n   0.286/0.869n   0.697/0.438n
dV/dt_f   0.457/1.067n   0.302/1.573n   0.670/0.702n
R_load = 50.000
[Rising Waveform]
R_fixture= 50.000
V_fixture= 0.0
V_fixture_min= 0.0
V_fixture_max= 0.0
|time   V(typ)   V(min)   V(max)
0s        2.016mV    1.415mV    2.955mV
758ps     2.329mV    1.416mV    17.46mV
1.155ns   -5.989mV   1.888mV    736.5mV
1.349ns   18.54mV    855.8uV    940.2mV
1.648ns   215mV      -9.025mV   1.075V
1.844ns   402.1mV    -4.026mV   1.112V
2.144ns   559.5mV    2.456mV    1.141V
3.349ns   690.4mV    374.5mV    1.163V
4.345ns   698.2mV    461.6mV    1.164V
20ns      699.6mV    477.4mV    1.165V
[Rising Waveform]
R_fixture= 50.000
V_fixture= 2.500
V_fixture_min= 2.380
V_fixture_max= 2.630
|time   V(typ)   V(min)   V(max)
0s        1.738V     1.877V     1.514V
516ps     1.738V     1.877V     1.521V
678ps     1.739V     1.877V     2.079V
872ps     1.737V     1.877V     2.429V
1.114ns   2.192V     1.877V     2.573V
1.451ns   2.406V     1.889V     2.613V
1.692ns   2.459V     2.178V     2.621V
1.841ns   2.473V     2.263V     2.624V
2.816ns   2.497V     2.366V     2.63V
20ns      2.5V       2.38V      2.63V
[Falling Waveform]
R_fixture= 50.000
V_fixture= 2.500
V_fixture_min= 2.380
V_fixture_max= 2.630
|time   V(typ)   V(min)   V(max)
0s        2.5V       2.38V      2.63V
752ps     2.499V     2.38V      2.645V
1.077ns   2.526V     2.38V      2.357V
1.311ns   2.512V     2.379V     2.035V
1.681ns   2.393V     2.385V     1.753V
2.199ns   2.108V     2.386V     1.588V
2.789ns   1.899V     2.323V     1.533V
4.043ns   1.761V     2.043V     1.515V
5.539ns   1.74V      1.913V     1.514V
20ns      1.738V     1.877V     1.514V
[Falling Waveform]
R_fixture= 50.000
V_fixture= 0.0
V_fixture_min= 0.0
V_fixture_max= 0.0
|time   V(typ)   V(min)   V(max)
0s        699.6mV    477.4mV    1.165V
556ps     699.6mV    477.3mV    1.156V
733ps     699.4mV    477.4mV    559.7mV
952ps     702.5mV    477.4mV    192.5mV
1.235ns   279.4mV    477.2mV    43.11mV
1.505ns   109.8mV    477.7mV    16.66mV
1.687ns   55.64mV    468.6mV    10.54mV
2.106ns   14.99mV    117.9mV    4.785mV
2.998ns   3.575mV    12.82mV    3.138mV
20ns      2.016mV    1.415mV    2.955mV
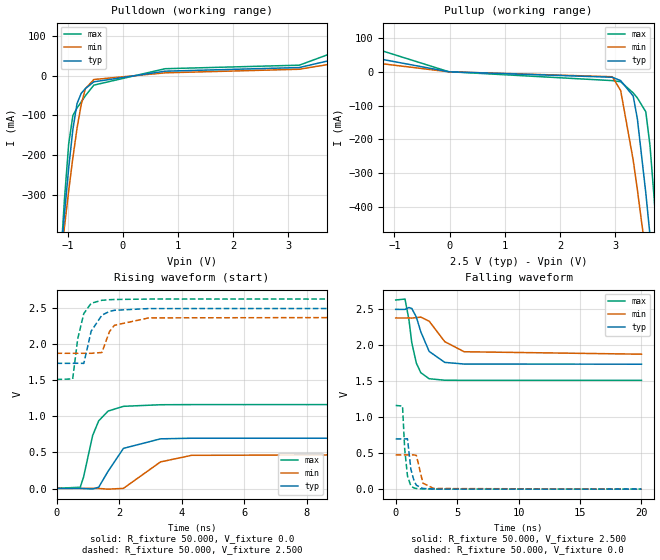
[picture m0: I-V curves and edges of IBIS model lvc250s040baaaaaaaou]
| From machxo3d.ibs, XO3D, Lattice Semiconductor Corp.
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|   Model lvc250s040baaaaaaaou
[Model] lvc250s040baaaaaaaou
Model_type Output
Polarity   Non-Inverting
Enable   Active-High
Vmeas =  1.250V
Cref =  0.0F
Rref =  1.000M
Vref =  0.0V
C_comp   4.200pF   3.800pF   7.500pF
[Temperature Range]   25.000   0.105k   -40.000
[Voltage Range]   2.500V   2.380V   2.630V
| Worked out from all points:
|   slope of the pulldown table from 0 to 0.375 V, typ, clamps not added: 54.3 ohm
|   slope of the pullup table from 0 to 0.375 V, typ, clamps not added: 64.7 ohm
|   rising waveform, R_fixture 50.000, V_fixture 0.0: 20-80 % time 603ps typ, 875ps min, 437ps max; typ from 0.002 V to 0.7 V
|   rising waveform, R_fixture 50.000, V_fixture 2.500: 20-80 % time 350ps typ, 362ps min, 275ps max; typ from 1.74 V to 2.5 V
|   falling waveform, R_fixture 50.000, V_fixture 2.500: 20-80 % time 1.05ns typ, 1.58ns min, 706ps max; typ from 2.5 V to 1.74 V
|   falling waveform, R_fixture 50.000, V_fixture 0.0: 20-80 % time 360ps typ, 395ps min, 298ps max; typ from 0.7 V to 0.002 V
[Pulldown]
|Voltage   I(typ)   I(min)   I(max)
-2.5V     -2.991A    -2.35A     -4.091A
-1.132V   -472.6mA   -475.7mA   -480.1mA
-1.056V   -348.1mA   -381.3mA   -311.4mA
-980mV    -233.1mA   -290.9mA   -172.6mA
-904mV    -135.4mA   -206.7mA   -100.3mA
-828mV    -69.73mA   -132.1mA   -80.99mA
-752mV    -44.08mA   -71.8mA    -65.95mA
-676mV    -32.09mA   -32.23mA   -50mA
-524mV    -15.14mA   -9.304mA   -23.47mA
768mV     11.7mA     7.532mA    17.93mA
3.2V      20.89mA    16.59mA    26.85mA
5V        78.87mA    57.84mA    119.2mA
[Pullup]
|Voltage   I(typ)   I(min)   I(max)
-2.5V     75.99mA    49.36mA    128.1mA
-16mV     284.4uA    205uA      457.2uA
2.948V    -16.03mA   -14.51mA   -26.03mA
3.1V      -25.99mA   -55.21mA   -29.31mA
3.328V    -71.92mA   -262.4mA   -62.64mA
3.404V    -140.6mA   -351.2mA   -77.7mA
3.556V    -359.8mA   -541mA     -118.7mA
3.632V    -485.6mA   -639.6mA   -219.2mA
3.708V    -616.1mA   -739.9mA   -376.5mA
3.784V    -749.8mA   -841.4mA   -554.7mA
3.86V     -885.5mA   -943.8mA   -742.2mA
5V        -3.006A    -2.53A     -3.767A
[Ramp]
| variable   typ   min   max
dV/dt_r   0.419/0.610n   0.286/0.863n   0.697/0.439n
dV/dt_f   0.457/1.067n   0.302/1.589n   0.670/0.702n
R_load = 50.000
[Rising Waveform]
R_fixture= 50.000
V_fixture= 0.0
V_fixture_min= 0.0
V_fixture_max= 0.0
|time   V(typ)   V(min)   V(max)
0s        2.016mV    1.415mV    2.955mV
758ps     2.329mV    1.412mV    17.47mV
865ps     -843uV     1.412mV    160.7mV
1.155ns   -5.988mV   1.884mV    736.5mV
1.349ns   18.55mV    856.2uV    940.2mV
1.649ns   239.7mV    -9.05mV    1.075V
2.138ns   557mV      1.859mV    1.141V
3.324ns   689.7mV    369.5mV    1.163V
4.321ns   698.2mV    460.9mV    1.165V
20ns      699.6mV    477.4mV    1.165V
[Rising Waveform]
R_fixture= 50.000
V_fixture= 2.500
V_fixture_min= 2.380
V_fixture_max= 2.630
|time   V(typ)   V(min)   V(max)
0s        1.738V     1.877V     1.514V
516ps     1.738V     1.877V     1.521V
678ps     1.739V     1.877V     2.079V
872ps     1.737V     1.877V     2.429V
1.108ns   2.185V     1.877V     2.572V
1.45ns    2.406V     1.888V     2.613V
1.693ns   2.459V     2.179V     2.621V
1.849ns   2.474V     2.266V     2.624V
2.953ns   2.498V     2.369V     2.63V
20ns      2.5V       2.38V      2.63V
[Falling Waveform]
R_fixture= 50.000
V_fixture= 2.500
V_fixture_min= 2.380
V_fixture_max= 2.630
|time   V(typ)   V(min)   V(max)
0s        2.5V       2.38V      2.63V
758ps     2.499V     2.38V      2.643V
1.077ns   2.526V     2.38V      2.357V
1.311ns   2.512V     2.379V     2.035V
1.681ns   2.393V     2.385V     1.753V
2.042ns   2.189V     2.392V     1.62V
2.722ns   1.916V     2.336V     1.536V
3.993ns   1.763V     2.051V     1.515V
5.575ns   1.74V      1.911V     1.514V
20ns      1.738V     1.877V     1.514V
[Falling Waveform]
R_fixture= 50.000
V_fixture= 0.0
V_fixture_min= 0.0
V_fixture_max= 0.0
|time   V(typ)   V(min)   V(max)
0s        699.6mV    477.4mV    1.165V
556ps     699.7mV    477.3mV    1.156V
733ps     699.4mV    477.5mV    559.5mV
958ps     701.9mV    477.5mV    186.2mV
1.238ns   276.3mV    477.3mV    43.11mV
1.505ns   109.8mV    477.7mV    16.73mV
1.687ns   55.66mV    468.6mV    10.59mV
2.216ns   11.56mV    84.62mV    4.281mV
3.111ns   3.282mV    10.39mV    3.079mV
20ns      2.016mV    1.415mV    2.955mV
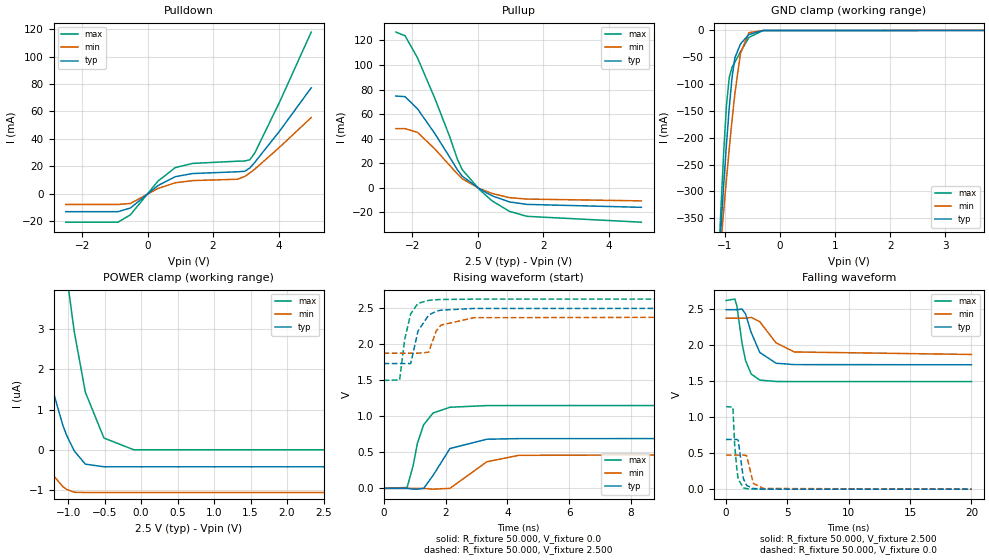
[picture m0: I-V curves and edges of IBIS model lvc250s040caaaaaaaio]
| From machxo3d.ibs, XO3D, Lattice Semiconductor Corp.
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|   Model lvc250s040caaaaaaaio
[Model] lvc250s040caaaaaaaio
Model_type I/O
Polarity   Non-Inverting
Enable   Active-Low
Vinl =  0.700V
Vinh =  1.700V
Vmeas =  1.250V
Cref =  0.0F
Rref =  1.000M
Vref =  0.0V
C_comp   4.200pF   3.800pF   7.500pF
[Temperature Range]   25.000   0.105k   -40.000
[Voltage Range]   2.500V   2.380V   2.630V
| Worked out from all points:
|   slope of the pulldown table from 0 to 0.375 V, typ, clamps not added: 54.4 ohm
|   slope of the pullup table from 0 to 0.375 V, typ, clamps not added: 65.1 ohm
|   GND clamp passes 1 mA (typ) near -0.43 V on its own axis
|   rising waveform, R_fixture 50.000, V_fixture 0.0: 20-80 % time 599ps typ, 870ps min, 438ps max; typ from 0 V to 0.691 V
|   rising waveform, R_fixture 50.000, V_fixture 2.500: 20-80 % time 356ps typ, 364ps min, 278ps max; typ from 1.73 V to 2.5 V
|   falling waveform, R_fixture 50.000, V_fixture 2.500: 20-80 % time 1.06ns typ, 1.56ns min, 701ps max; typ from 2.5 V to 1.73 V
|   falling waveform, R_fixture 50.000, V_fixture 0.0: 20-80 % time 350ps typ, 387ps min, 292ps max; typ from 0.691 V to 0 V
[Pulldown]
|Voltage   I(typ)   I(min)   I(max)
-2.5V     -13.08mA   -7.815mA   -20.75mA
-904mV    -13.08mA   -7.815mA   -20.75mA
-524mV    -10.41mA   -7.109mA   -15.34mA
312mV     5.902mA    3.803mA    9.102mA
844mV     12.43mA    8.006mA    19.04mA
1.376V    14.74mA    9.586mA    22.12mA
2.744V    16.02mA    10.57mA    23.73mA
2.972V    16.41mA    12.64mA    23.88mA
3.124V    18.78mA    15.15mA    24.77mA
3.276V    22.93mA    17.94mA    29.79mA
4.036V    45.77mA    34.01mA    67.03mA
5V        77.27mA    55.58mA    117.9mA
[Pullup]
|Voltage   I(typ)   I(min)   I(max)
-2.5V     74.72mA    48.19mA    126.8mA
-2.22V    74.19mA    48.19mA    123.8mA
-1.84V    64.26mA    45.06mA    105.8mA
-1.308V   44.03mA    31.55mA    72.6mA
-852mV    24.68mA    18.03mA    41.27mA
-624mV    14.69mA    11.35mA    23.35mA
-472mV    9.375mA    7.275mA    14.66mA
60mV      -1.036mA   -745uA     -1.668mA
440mV     -6.588mA   -4.693mA   -10.74mA
972mV     -11.57mA   -8.084mA   -19.27mA
1.504V    -13.57mA   -9.251mA   -23.3mA
5V        -15.96mA   -10.7mA    -28.07mA
[GND_clamp]
|Voltage   I(typ)   I(min)   I(max)
-2.5V     -2.99A     -2.35A     -4.091A
-1.123V   -455.1mA   -463.2mA   -453.7mA
-1.072V   -370.5mA   -399.5mA   -336.3mA
-1.021V   -289.2mA   -337.4mA   -228.6mA
-970mV    -212.6mA   -277.4mA   -140mA
-919mV    -143.6mA   -220.1mA   -87.4mA
-868mV    -87.39mA   -166.5mA   -68.45mA
-817mV    -50.94mA   -117.8mA   -59.13mA
-715mV    -24.99mA   -42.37mA   -39.7mA
-562mV    -7.608mA   -4.125mA   -12.95mA
-307mV    -97.66uA   -51.76uA   -173.8uA
5V        114uA      49.34uA    266.8uA
[POWER_clamp]
|Voltage   I(typ)   I(min)   I(max)
-2.5V     22.27uA    8.76uA     64.97uA
-2.141V   14.03uA    4.838uA    43.67uA
-1.835V   8.45uA     2.288uA    28.47uA
-1.58V    4.901uA    736nA      18.31uA
-1.274V   1.887uA    -485.6nA   9.321uA
-1.07V    594.4nA    -923.9nA   5.173uA
-1.019V   355.1nA    -987.6nA   4.351uA
-917mV    -26.39nA   -1.058uA   2.951uA
-764mV    -358.7nA   -1.065uA   1.434uA
-509mV    -424.7nA   -1.065uA   291.6nA
-101mV    -424.7nA   -1.065uA   0A
2.5V      -424.7nA   -1.065uA   0A
[Ramp]
| variable   typ   min   max
dV/dt_r   0.415/0.606n   0.284/0.862n   0.689/0.439n
dV/dt_f   0.460/1.067n   0.303/1.585n   0.677/0.700n
R_load = 50.000
[Rising Waveform]
R_fixture= 50.000
V_fixture= 0.0
V_fixture_min= 0.0
V_fixture_max= 0.0
|time   V(typ)   V(min)   V(max)
0s        9.102nV    62.88nV    33.47nV
759ps     347.9uV    2.949uV    12.62mV
956ps     -10.74mV   26.97uV    320.6mV
1.091ns   -10.78mV   240.6uV    623.9mV
1.292ns   -684uV     182.9uV    880.6mV
1.597ns   178.9mV    -10.87mV   1.045V
2.143ns   552.3mV    217.6uV    1.125V
3.338ns   681.8mV    369mV      1.148V
4.365ns   690mV      458.4mV    1.149V
20ns      691.3mV    473.6mV    1.149V
[Rising Waveform]
R_fixture= 50.000
V_fixture= 2.500
V_fixture_min= 2.380
V_fixture_max= 2.630
|time   V(typ)   V(min)   V(max)
0s        1.731V     1.874V     1.497V
516ps     1.731V     1.874V     1.504V
679ps     1.731V     1.874V     2.064V
874ps     1.73V      1.874V     2.42V
1.109ns   2.179V     1.874V     2.565V
1.455ns   2.403V     1.888V     2.607V
1.697ns   2.456V     2.18V      2.616V
1.85ns    2.471V     2.264V     2.619V
2.93ns    2.495V     2.367V     2.624V
20ns      2.497V     2.379V     2.625V
[Falling Waveform]
R_fixture= 50.000
V_fixture= 2.500
V_fixture_min= 2.380
V_fixture_max= 2.630
|time   V(typ)   V(min)   V(max)
0s        2.497V     2.379V     2.625V
721ps     2.497V     2.379V     2.645V
883ps     2.497V     2.379V     2.549V
1.304ns   2.507V     2.378V     2.029V
1.59ns    2.436V     2.378V     1.79V
2.052ns   2.178V     2.39V      1.601V
2.75ns    1.902V     2.329V     1.518V
4.078ns   1.752V     2.035V     1.498V
5.563ns   1.733V     1.909V     1.497V
20ns      1.731V     1.874V     1.497V
[Falling Waveform]
R_fixture= 50.000
V_fixture= 0.0
V_fixture_min= 0.0
V_fixture_max= 0.0
|time   V(typ)   V(min)   V(max)
0s        691.3mV    473.6mV    1.149V
556ps     691.3mV    473.5mV    1.141V
701ps     691.2mV    473.6mV    622.5mV
895ps     691.9mV    473.6mV    251.5mV
994ps     677.5mV    473.6mV    138mV
1.415ns   143.8mV    473.9mV    17.87mV
1.682ns   51.74mV    466.8mV    6.991mV
2.218ns   9.013mV    80.87mV    1.295mV
3.069ns   1.28mV     9.201mV    182.2uV
20ns      12.72nV    113.1nV    30.87nV
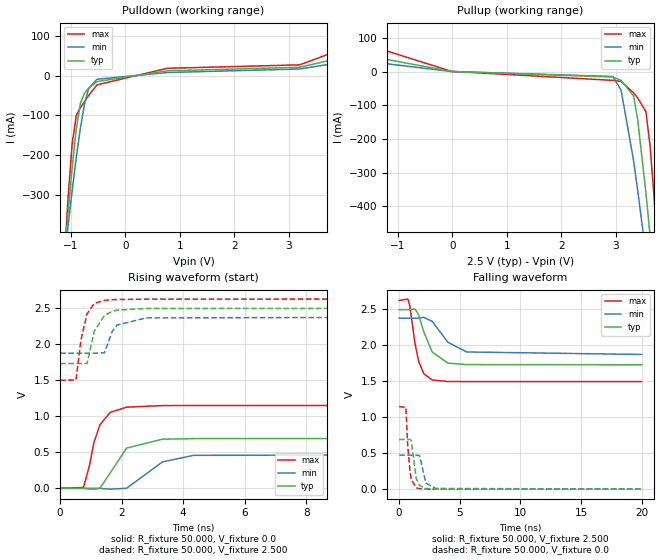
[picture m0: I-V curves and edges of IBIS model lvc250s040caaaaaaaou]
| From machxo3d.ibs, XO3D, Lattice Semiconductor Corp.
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|   Model lvc250s040caaaaaaaou
[Model] lvc250s040caaaaaaaou
Model_type Output
Polarity   Non-Inverting
Enable   Active-High
Vmeas =  1.250V
Cref =  0.0F
Rref =  1.000M
Vref =  0.0V
C_comp   4.200pF   3.800pF   7.500pF
[Temperature Range]   25.000   0.105k   -40.000
[Voltage Range]   2.500V   2.380V   2.630V
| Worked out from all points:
|   slope of the pulldown table from 0 to 0.375 V, typ, clamps not added: 53.8 ohm
|   slope of the pullup table from 0 to 0.375 V, typ, clamps not added: 65.1 ohm
|   rising waveform, R_fixture 50.000, V_fixture 0.0: 20-80 % time 600ps typ, 874ps min, 438ps max; typ from 0 V to 0.691 V
|   rising waveform, R_fixture 50.000, V_fixture 2.500: 20-80 % time 353ps typ, 362ps min, 278ps max; typ from 1.73 V to 2.5 V
|   falling waveform, R_fixture 50.000, V_fixture 2.500: 20-80 % time 1.07ns typ, 1.57ns min, 703ps max; typ from 2.5 V to 1.73 V
|   falling waveform, R_fixture 50.000, V_fixture 0.0: 20-80 % time 351ps typ, 388ps min, 292ps max; typ from 0.691 V to 0 V
[Pulldown]
|Voltage   I(typ)   I(min)   I(max)
-2.5V     -2.991A    -2.35A     -4.091A
-1.132V   -472.7mA   -475.7mA   -480.1mA
-1.056V   -348.1mA   -381.3mA   -311.4mA
-980mV    -233.1mA   -290.9mA   -172.7mA
-904mV    -135.4mA   -206.7mA   -100.3mA
-828mV    -69.74mA   -132.1mA   -81mA
-752mV    -44.09mA   -71.81mA   -65.96mA
-676mV    -32.1mA    -32.24mA   -50.01mA
-524mV    -15.15mA   -9.318mA   -23.48mA
768mV     11.87mA    7.615mA    18.3mA
3.2V      20.91mA    16.55mA    26.95mA
5V        77.41mA    55.64mA    118.3mA
[Pullup]
|Voltage   I(typ)   I(min)   I(max)
-2.5V     74.85mA    48.24mA    127.1mA
-16mV     387.7uA    243.2uA    703uA
2.948V    -16.04mA   -14.52mA   -26.02mA
3.1V      -26mA      -55.22mA   -29.32mA
3.328V    -71.93mA   -262.4mA   -62.65mA
3.404V    -140.6mA   -351.2mA   -77.71mA
3.556V    -359.8mA   -541mA     -118.7mA
3.632V    -485.6mA   -639.6mA   -219.2mA
3.708V    -616.1mA   -739.9mA   -376.5mA
3.784V    -749.8mA   -841.4mA   -554.7mA
3.86V     -885.5mA   -943.8mA   -742.2mA
5V        -3.006A    -2.53A     -3.767A
[Ramp]
| variable   typ   min   max
dV/dt_r   0.415/0.606n   0.284/0.862n   0.689/0.439n
dV/dt_f   0.460/1.067n   0.303/1.585n   0.677/0.700n
R_load = 50.000
[Rising Waveform]
R_fixture= 50.000
V_fixture= 0.0
V_fixture_min= 0.0
V_fixture_max= 0.0
|time   V(typ)   V(min)   V(max)
0s        9.102nV    62.88nV    33.47nV
759ps     311.4uV    -1.05uV    12.62mV
956ps     -10.57mV   23.34uV    320.7mV
1.094ns   -10.74mV   230.4uV    629.1mV
1.292ns   -681.6uV   195.8uV    880.6mV
1.625ns   212.4mV    -11.19mV   1.053V
2.161ns   558.5mV    1.48mV     1.126V
3.326ns   681.6mV    366.6mV    1.148V
4.337ns   689.9mV    457.6mV    1.149V
20ns      691.3mV    473.6mV    1.149V
[Rising Waveform]
R_fixture= 50.000
V_fixture= 2.500
V_fixture_min= 2.380
V_fixture_max= 2.630
|time   V(typ)   V(min)   V(max)
0s        1.731V     1.874V     1.497V
516ps     1.731V     1.874V     1.504V
679ps     1.731V     1.874V     2.064V
874ps     1.73V      1.874V     2.42V
1.109ns   2.179V     1.874V     2.565V
1.441ns   2.398V     1.88V      2.606V
1.697ns   2.456V     2.18V      2.616V
1.85ns    2.471V     2.264V     2.619V
2.798ns   2.494V     2.364V     2.624V
20ns      2.497V     2.379V     2.625V
[Falling Waveform]
R_fixture= 50.000
V_fixture= 2.500
V_fixture_min= 2.380
V_fixture_max= 2.630
|time   V(typ)   V(min)   V(max)
0s        2.497V     2.379V     2.625V
721ps     2.497V     2.379V     2.645V
883ps     2.497V     2.379V     2.549V
1.304ns   2.507V     2.378V     2.029V
1.603ns   2.43V      2.379V     1.782V
2.024ns   2.193V     2.391V     1.608V
2.723ns   1.909V     2.335V     1.519V
4.02ns    1.754V     2.044V     1.498V
5.564ns   1.733V     1.909V     1.497V
20ns      1.731V     1.874V     1.497V
[Falling Waveform]
R_fixture= 50.000
V_fixture= 0.0
V_fixture_min= 0.0
V_fixture_max= 0.0
|time   V(typ)   V(min)   V(max)
0s        691.3mV    473.6mV    1.149V
556ps     691.3mV    473.6mV    1.14V
701ps     691.2mV    473.7mV    622.6mV
895ps     691.9mV    473.7mV    251.8mV
994ps     677.5mV    473.6mV    138.3mV
1.411ns   145.8mV    473.9mV    18.13mV
1.685ns   51.34mV    465.6mV    7.2mV
2.204ns   9.297mV    84.29mV    1.384mV
3.017ns   1.379mV    10.31mV    213.5uV
20ns      12.15nV    109.2nV    31.36nV
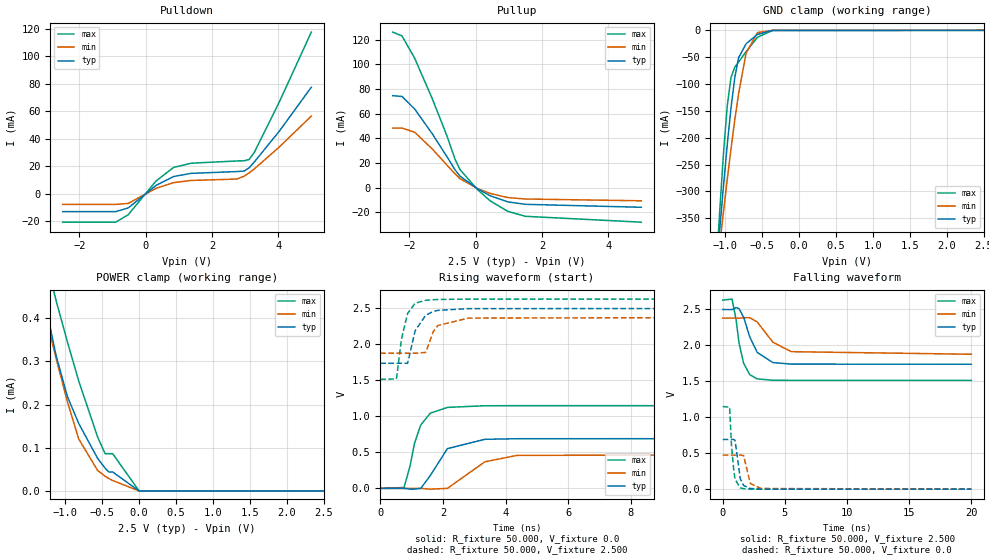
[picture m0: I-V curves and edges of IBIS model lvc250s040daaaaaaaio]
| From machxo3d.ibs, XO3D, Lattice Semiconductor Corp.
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|   Model lvc250s040daaaaaaaio
[Model] lvc250s040daaaaaaaio
Model_type I/O
Polarity   Non-Inverting
Enable   Active-Low
Vinl =  0.700V
Vinh =  1.700V
Vmeas =  1.250V
Cref =  0.0F
Rref =  1.000M
Vref =  0.0V
C_comp   4.200pF   3.800pF   7.500pF
[Temperature Range]   25.000   0.105k   -40.000
[Voltage Range]   2.500V   2.380V   2.630V
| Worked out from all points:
|   slope of the pulldown table from 0 to 0.375 V, typ, clamps not added: 54.4 ohm
|   slope of the pullup table from 0 to 0.375 V, typ, clamps not added: 65.1 ohm
|   GND clamp passes 1 mA (typ) near -0.43 V on its own axis
|   POWER clamp passes 1 mA (typ) near -1.90 V on its own axis
|   rising waveform, R_fixture 50.000, V_fixture 0.0: 20-80 % time 599ps typ, 870ps min, 438ps max; typ from 0 V to 0.691 V
|   rising waveform, R_fixture 50.000, V_fixture 2.500: 20-80 % time 350ps typ, 361ps min, 275ps max; typ from 1.74 V to 2.5 V
|   falling waveform, R_fixture 50.000, V_fixture 2.500: 20-80 % time 1.05ns typ, 1.57ns min, 702ps max; typ from 2.5 V to 1.74 V
|   falling waveform, R_fixture 50.000, V_fixture 0.0: 20-80 % time 350ps typ, 387ps min, 292ps max; typ from 0.691 V to 0 V
[Pulldown]
|Voltage   I(typ)   I(min)   I(max)
-2.5V     -13.08mA   -7.815mA   -20.75mA
-904mV    -13.08mA   -7.815mA   -20.75mA
-524mV    -10.41mA   -7.109mA   -15.34mA
312mV     5.902mA    3.803mA    9.102mA
844mV     12.43mA    8.006mA    19.04mA
1.376V    14.74mA    9.586mA    22.12mA
2.744V    16.02mA    10.57mA    23.73mA
2.972V    16.42mA    12.64mA    23.88mA
3.124V    18.76mA    15.12mA    24.81mA
3.276V    22.89mA    17.87mA    29.77mA
4.036V    45.44mA    33.92mA    66.69mA
5V        77.33mA    56.37mA    117.4mA
[Pullup]
|Voltage   I(typ)   I(min)   I(max)
-2.5V     74.64mA    48.35mA    126.3mA
-2.22V    74.04mA    48.35mA    123.2mA
-1.84V    63.93mA    45.06mA    105.2mA
-1.308V   43.79mA    31.42mA    72.33mA
-852mV    24.62mA    17.98mA    41.17mA
-624mV    14.67mA    11.34mA    23.35mA
-472mV    9.383mA    7.274mA    14.7mA
60mV      -1.036mA   -745uA     -1.668mA
440mV     -6.588mA   -4.693mA   -10.74mA
972mV     -11.57mA   -8.084mA   -19.27mA
1.504V    -13.57mA   -9.251mA   -23.3mA
5V        -15.96mA   -10.7mA    -28.07mA
[GND_clamp]
|Voltage   I(typ)   I(min)   I(max)
-2.5V     -2.99A     -2.35A     -4.091A
-1.123V   -455.1mA   -463.2mA   -453.7mA
-1.072V   -370.5mA   -399.5mA   -336.3mA
-1.021V   -289.2mA   -337.4mA   -228.6mA
-970mV    -212.6mA   -277.4mA   -140mA
-919mV    -143.6mA   -220.1mA   -87.4mA
-868mV    -87.39mA   -166.5mA   -68.45mA
-817mV    -50.94mA   -117.8mA   -59.13mA
-715mV    -24.99mA   -42.37mA   -39.7mA
-562mV    -7.608mA   -4.125mA   -12.95mA
-358mV    -194.9uA   -98.36uA   -303.6uA
2.5V      13.17nA    0A         -19.29uA
[POWER_clamp]
|Voltage   I(typ)   I(min)   I(max)
-2.5V     1.538mA    1.365mA    2.125mA
-1.325V   482.6uA    450.2uA    591.5uA
-1.274V   438.4uA    413.8uA    546.6uA
-1.121V   313.5uA    307.1uA    441uA
-968mV    218.6uA    206.5uA    345.2uA
-815mV    156.3uA    120.3uA    254.8uA
-560mV    75.6uA     47.55uA    125.2uA
-458mV    52.75uA    33.88uA    86.35uA
-407mV    44.01uA    28.68uA    86.35uA
-356mV    44.01uA    24.21uA    86.35uA
1mV       0A         0A         141nA
2.5V      0A         0A         0A
[Ramp]
| variable   typ   min   max
dV/dt_r   0.415/0.606n   0.284/0.862n   0.689/0.439n
dV/dt_f   0.457/1.067n   0.302/1.569n   0.670/0.702n
R_load = 50.000
[Rising Waveform]
R_fixture= 50.000
V_fixture= 0.0
V_fixture_min= 0.0
V_fixture_max= 0.0
|time   V(typ)   V(min)   V(max)
0s        9.102nV    62.88nV    33.47nV
759ps     347.9uV    2.919uV    12.62mV
956ps     -10.74mV   26.97uV    320.6mV
1.091ns   -10.78mV   240.6uV    623.9mV
1.292ns   -684uV     182.9uV    880.6mV
1.597ns   178.9mV    -10.87mV   1.045V
2.143ns   552.3mV    217.6uV    1.125V
3.338ns   681.8mV    369mV      1.148V
4.365ns   690mV      458.4mV    1.149V
20ns      691.3mV    473.6mV    1.149V
[Rising Waveform]
R_fixture= 50.000
V_fixture= 2.500
V_fixture_min= 2.380
V_fixture_max= 2.630
|time   V(typ)   V(min)   V(max)
0s        1.738V     1.877V     1.514V
516ps     1.738V     1.877V     1.521V
678ps     1.739V     1.877V     2.079V
872ps     1.737V     1.877V     2.429V
1.114ns   2.192V     1.877V     2.573V
1.451ns   2.406V     1.889V     2.613V
1.692ns   2.459V     2.178V     2.621V
1.841ns   2.473V     2.263V     2.624V
2.816ns   2.497V     2.366V     2.63V
20ns      2.5V       2.38V      2.63V
[Falling Waveform]
R_fixture= 50.000
V_fixture= 2.500
V_fixture_min= 2.380
V_fixture_max= 2.630
|time   V(typ)   V(min)   V(max)
0s        2.5V       2.38V      2.63V
752ps     2.499V     2.38V      2.645V
1.077ns   2.526V     2.38V      2.357V
1.311ns   2.512V     2.379V     2.035V
1.681ns   2.393V     2.385V     1.753V
2.178ns   2.118V     2.386V     1.592V
2.777ns   1.902V     2.326V     1.534V
4.039ns   1.761V     2.044V     1.515V
5.523ns   1.74V      1.913V     1.514V
20ns      1.738V     1.877V     1.514V
[Falling Waveform]
R_fixture= 50.000
V_fixture= 0.0
V_fixture_min= 0.0
V_fixture_max= 0.0
|time   V(typ)   V(min)   V(max)
0s        691.3mV    473.6mV    1.149V
556ps     691.3mV    473.5mV    1.141V
701ps     691.2mV    473.6mV    622.5mV
895ps     691.9mV    473.6mV    251.5mV
994ps     677.5mV    473.6mV    138mV
1.415ns   143.8mV    473.9mV    17.87mV
1.682ns   51.74mV    466.8mV    6.991mV
2.218ns   9.013mV    80.87mV    1.295mV
3.069ns   1.28mV     9.201mV    182.2uV
20ns      12.72nV    113.1nV    30.87nV
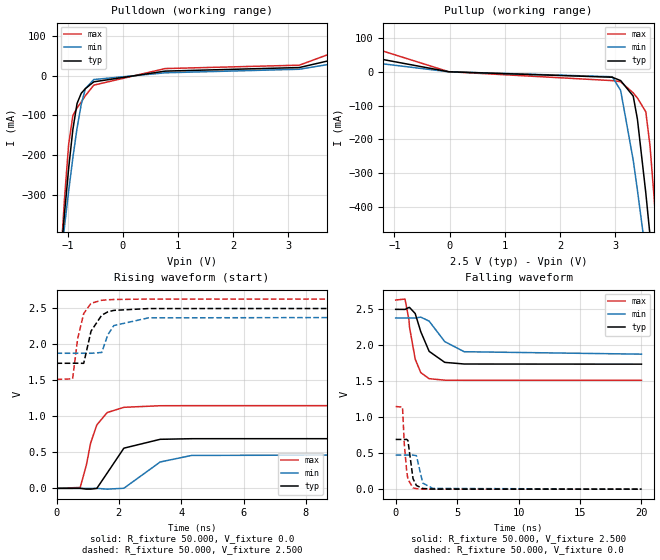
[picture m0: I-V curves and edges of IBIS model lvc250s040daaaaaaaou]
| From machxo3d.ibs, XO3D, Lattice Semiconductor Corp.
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|   Model lvc250s040daaaaaaaou
[Model] lvc250s040daaaaaaaou
Model_type Output
Polarity   Non-Inverting
Enable   Active-High
Vmeas =  1.250V
Cref =  0.0F
Rref =  1.000M
Vref =  0.0V
C_comp   4.200pF   3.800pF   7.500pF
[Temperature Range]   25.000   0.105k   -40.000
[Voltage Range]   2.500V   2.380V   2.630V
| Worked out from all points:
|   slope of the pulldown table from 0 to 0.375 V, typ, clamps not added: 53.8 ohm
|   slope of the pullup table from 0 to 0.375 V, typ, clamps not added: 64.7 ohm
|   rising waveform, R_fixture 50.000, V_fixture 0.0: 20-80 % time 600ps typ, 874ps min, 438ps max; typ from 0 V to 0.691 V
|   rising waveform, R_fixture 50.000, V_fixture 2.500: 20-80 % time 350ps typ, 363ps min, 275ps max; typ from 1.74 V to 2.5 V
|   falling waveform, R_fixture 50.000, V_fixture 2.500: 20-80 % time 1.05ns typ, 1.58ns min, 703ps max; typ from 2.5 V to 1.74 V
|   falling waveform, R_fixture 50.000, V_fixture 0.0: 20-80 % time 351ps typ, 388ps min, 292ps max; typ from 0.691 V to 0 V
[Pulldown]
|Voltage   I(typ)   I(min)   I(max)
-2.5V     -2.991A    -2.35A     -4.091A
-1.132V   -472.7mA   -475.7mA   -480.1mA
-1.056V   -348.1mA   -381.3mA   -311.4mA
-980mV    -233.1mA   -290.9mA   -172.7mA
-904mV    -135.4mA   -206.7mA   -100.3mA
-828mV    -69.74mA   -132.1mA   -81mA
-752mV    -44.09mA   -71.81mA   -65.96mA
-676mV    -32.1mA    -32.24mA   -50.01mA
-524mV    -15.15mA   -9.318mA   -23.48mA
768mV     11.87mA    7.615mA    18.3mA
3.2V      20.89mA    16.59mA    26.85mA
5V        78.87mA    57.84mA    119.2mA
[Pullup]
|Voltage   I(typ)   I(min)   I(max)
-2.5V     75.99mA    49.36mA    128.1mA
-16mV     284.4uA    205uA      457.2uA
2.948V    -16.04mA   -14.52mA   -26.02mA
3.1V      -26mA      -55.22mA   -29.32mA
3.328V    -71.93mA   -262.4mA   -62.65mA
3.404V    -140.6mA   -351.2mA   -77.71mA
3.556V    -359.8mA   -541mA     -118.7mA
3.632V    -485.6mA   -639.6mA   -219.2mA
3.708V    -616.1mA   -739.9mA   -376.5mA
3.784V    -749.8mA   -841.4mA   -554.7mA
3.86V     -885.5mA   -943.8mA   -742.2mA
5V        -3.006A    -2.53A     -3.767A
[Ramp]
| variable   typ   min   max
dV/dt_r   0.415/0.606n   0.284/0.862n   0.689/0.439n
dV/dt_f   0.457/1.067n   0.302/1.589n   0.670/0.702n
R_load = 50.000
[Rising Waveform]
R_fixture= 50.000
V_fixture= 0.0
V_fixture_min= 0.0
V_fixture_max= 0.0
|time   V(typ)   V(min)   V(max)
0s        9.102nV    62.88nV    33.47nV
759ps     311.4uV    -1.046uV   12.62mV
956ps     -10.57mV   23.34uV    320.7mV
1.094ns   -10.74mV   230.4uV    629.1mV
1.292ns   -681.5uV   195.8uV    880.6mV
1.625ns   212.4mV    -11.19mV   1.053V
2.161ns   558.5mV    1.48mV     1.126V
3.326ns   681.6mV    366.6mV    1.148V
4.337ns   689.9mV    457.6mV    1.149V
20ns      691.3mV    473.6mV    1.149V
[Rising Waveform]
R_fixture= 50.000
V_fixture= 2.500
V_fixture_min= 2.380
V_fixture_max= 2.630
|time   V(typ)   V(min)   V(max)
0s        1.738V     1.877V     1.514V
516ps     1.738V     1.877V     1.521V
678ps     1.739V     1.877V     2.079V
872ps     1.737V     1.877V     2.429V
1.108ns   2.185V     1.877V     2.572V
1.45ns    2.406V     1.888V     2.613V
1.645ns   2.452V     2.133V     2.62V
1.839ns   2.473V     2.262V     2.624V
2.953ns   2.498V     2.369V     2.63V
20ns      2.5V       2.38V      2.63V
[Falling Waveform]
R_fixture= 50.000
V_fixture= 2.500
V_fixture_min= 2.380
V_fixture_max= 2.630
|time   V(typ)   V(min)   V(max)
0s        2.5V       2.38V      2.63V
758ps     2.499V     2.38V      2.643V
1.077ns   2.526V     2.38V      2.357V
1.124ns   2.527V     2.38V      2.254V
1.587ns   2.442V     2.379V     1.808V
2.042ns   2.189V     2.392V     1.62V
2.722ns   1.916V     2.336V     1.536V
3.993ns   1.763V     2.051V     1.515V
5.575ns   1.74V      1.911V     1.514V
20ns      1.738V     1.877V     1.514V
[Falling Waveform]
R_fixture= 50.000
V_fixture= 0.0
V_fixture_min= 0.0
V_fixture_max= 0.0
|time   V(typ)   V(min)   V(max)
0s        691.3mV    473.6mV    1.149V
556ps     691.3mV    473.6mV    1.14V
701ps     691.2mV    473.7mV    622.6mV
895ps     691.9mV    473.7mV    251.8mV
994ps     677.5mV    473.6mV    138.3mV
1.411ns   145.8mV    473.9mV    18.13mV
1.685ns   51.34mV    465.6mV    7.2mV
2.204ns   9.297mV    84.29mV    1.384mV
3.017ns   1.379mV    10.31mV    213.5uV
20ns      12.15nV    109.2nV    31.36nV
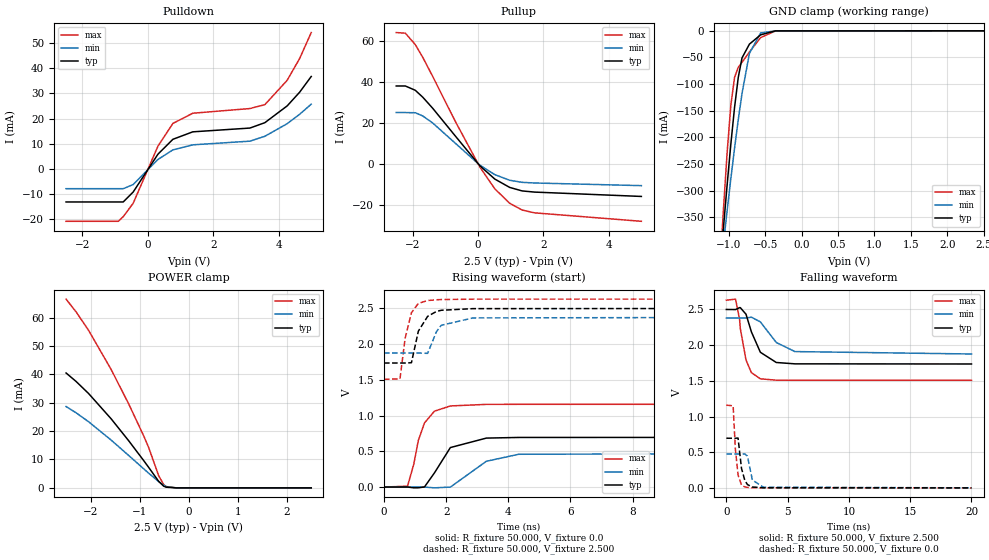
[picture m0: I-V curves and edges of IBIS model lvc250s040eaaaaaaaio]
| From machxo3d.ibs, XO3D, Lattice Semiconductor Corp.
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|   Model lvc250s040eaaaaaaaio
[Model] lvc250s040eaaaaaaaio
Model_type I/O
Polarity   Non-Inverting
Enable   Active-Low
Vinl =  0.700V
Vinh =  1.700V
Vmeas =  1.250V
Cref =  0.0F
Rref =  1.000M
Vref =  0.0V
C_comp   4.200pF   3.800pF   7.500pF
[Temperature Range]   25.000   0.105k   -40.000
[Voltage Range]   2.500V   2.380V   2.630V
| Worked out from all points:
|   slope of the pulldown table from 0 to 0.375 V, typ, clamps not added: 54.4 ohm
|   slope of the pullup table from 0 to 0.375 V, typ, clamps not added: 65.1 ohm
|   GND clamp passes 1 mA (typ) near -0.43 V on its own axis
|   POWER clamp passes 1 mA (typ) near -0.54 V on its own axis
|   rising waveform, R_fixture 50.000, V_fixture 0.0: 20-80 % time 604ps typ, 880ps min, 438ps max; typ from 0 V to 0.696 V
|   rising waveform, R_fixture 50.000, V_fixture 2.500: 20-80 % time 349ps typ, 361ps min, 276ps max; typ from 1.74 V to 2.5 V
|   falling waveform, R_fixture 50.000, V_fixture 2.500: 20-80 % time 1.06ns typ, 1.58ns min, 706ps max; typ from 2.5 V to 1.74 V
|   falling waveform, R_fixture 50.000, V_fixture 0.0: 20-80 % time 357ps typ, 392ps min, 296ps max; typ from 0.696 V to 0 V
[Pulldown]
|Voltage   I(typ)   I(min)   I(max)
-2.5V     -13.08mA   -7.815mA   -20.75mA
-904mV    -13.08mA   -7.815mA   -20.75mA
-752mV    -13.08mA   -7.815mA   -18.92mA
-448mV    -9.14mA    -6.165mA   -13.6mA
312mV     5.902mA    3.803mA    9.102mA
768mV     11.78mA    7.58mA     18.08mA
1.376V    14.74mA    9.586mA    22.12mA
3.124V    16.24mA    11.04mA    23.98mA
3.58V     18.37mA    12.97mA    25.51mA
4.264V    25.03mA    17.97mA    35.19mA
4.644V    30.45mA    21.69mA    43.8mA
5V        36.7mA     25.72mA    54.12mA
[Pullup]
|Voltage   I(typ)   I(min)   I(max)
-2.5V     37.85mA    24.9mA     63.87mA
-2.22V    37.85mA    24.9mA     63.58mA
-1.916V   35.74mA    24.81mA    57.99mA
-1.688V   32.39mA    23.26mA    51.82mA
-1.384V   27mA       19.82mA    42.52mA
-700mV    13.64mA    10.08mA    20.84mA
60mV      -1.036mA   -745uA     -1.668mA
516mV     -7.495mA   -5.327mA   -12.25mA
972mV     -11.57mA   -8.084mA   -19.27mA
1.352V    -13.27mA   -9.095mA   -22.58mA
1.732V    -13.84mA   -9.404mA   -23.95mA
5V        -15.96mA   -10.7mA    -28.07mA
[GND_clamp]
|Voltage   I(typ)   I(min)   I(max)
-2.5V     -2.99A     -2.35A     -4.091A
-1.123V   -455.1mA   -463.2mA   -453.6mA
-1.072V   -370.5mA   -399.5mA   -336.3mA
-1.021V   -289.1mA   -337.4mA   -228.5mA
-970mV    -212.6mA   -277.3mA   -139.9mA
-919mV    -143.6mA   -220.1mA   -87.34mA
-868mV    -87.35mA   -166.5mA   -68.39mA
-817mV    -50.9mA    -117.8mA   -59.07mA
-715mV    -24.94mA   -42.34mA   -39.63mA
-562mV    -7.547mA   -4.077mA   -12.85mA
-358mV    -114uA     -53.77uA   -172.8uA
2.5V      0A         0A         0A
[POWER_clamp]
|Voltage   I(typ)   I(min)   I(max)
-2.5V     40.49mA    28.66mA    66.53mA
-2.294V   37.48mA    26.44mA    61.99mA
-2.039V   33.22mA    23.28mA    55.47mA
-1.58V    24.32mA    16.83mA    41.7mA
-1.223V   16.6mA     11.41mA    29.58mA
-917mV    9.616mA    6.712mA    18.32mA
-815mV    7.205mA    5.171mA    14.19mA
-611mV    2.275mA    2.213mA    4.254mA
-509mV    589.4uA    929.1uA    1.152mA
-458mV    232.9uA    445.2uA    427.7uA
-254mV    3.785uA    4.472uA    4.114uA
2.5V      0A         0A         3.667nA
[Ramp]
| variable   typ   min   max
dV/dt_r   0.417/0.606n   0.285/0.862n   0.695/0.439n
dV/dt_f   0.459/1.070n   0.303/1.589n   0.673/0.702n
R_load = 50.000
[Rising Waveform]
R_fixture= 50.000
V_fixture= 0.0
V_fixture_min= 0.0
V_fixture_max= 0.0
|time   V(typ)   V(min)   V(max)
0s        9.431nV    63.61nV    34.88nV
759ps     351.8uV    3.005uV    12.47mV
960ps     -10.83mV   27.01uV    321.5mV
1.106ns   -10.33mV   237.7uV    653.1mV
1.304ns   1.646mV    -77.48uV   897.9mV
1.624ns   198.3mV    -11.2mV    1.062V
2.137ns   553mV      -333.7uV   1.135V
3.293ns   685.2mV    360.7mV    1.157V
4.337ns   694.3mV    459mV      1.158V
20ns      695.7mV    475.1mV    1.159V
[Rising Waveform]
R_fixture= 50.000
V_fixture= 2.500
V_fixture_min= 2.380
V_fixture_max= 2.630
|time   V(typ)   V(min)   V(max)
0s        1.736V     1.876V     1.508V
516ps     1.736V     1.876V     1.515V
679ps     1.736V     1.876V     2.076V
884ps     1.74V      1.876V     2.439V
1.107ns   2.182V     1.876V     2.571V
1.405ns   2.389V     1.871V     2.61V
1.691ns   2.458V     2.177V     2.621V
1.845ns   2.474V     2.264V     2.624V
2.862ns   2.497V     2.367V     2.63V
20ns      2.5V       2.38V      2.63V
[Falling Waveform]
R_fixture= 50.000
V_fixture= 2.500
V_fixture_min= 2.380
V_fixture_max= 2.630
|time   V(typ)   V(min)   V(max)
0s        2.5V       2.38V      2.63V
752ps     2.499V     2.38V      2.645V
1.083ns   2.526V     2.38V      2.36V
1.138ns   2.526V     2.38V      2.235V
1.607ns   2.433V     2.38V      1.791V
2.043ns   2.187V     2.392V     1.615V
2.777ns   1.9V       2.326V     1.528V
4.076ns   1.757V     2.037V     1.509V
5.594ns   1.738V     1.91V      1.508V
20ns      1.736V     1.876V     1.508V
[Falling Waveform]
R_fixture= 50.000
V_fixture= 0.0
V_fixture_min= 0.0
V_fixture_max= 0.0
|time   V(typ)   V(min)   V(max)
0s        695.7mV    475.1mV    1.159V
556ps     695.7mV    475mV      1.15V
735ps     695.4mV    475.1mV    548.1mV
956ps     698.2mV    475.1mV    181.8mV
1.238ns   272.3mV    474.9mV    38.75mV
1.509ns   104.3mV    475.4mV    13.13mV
1.72ns    46.27mV    445.7mV    6.563mV
2.124ns   11.88mV    109.1mV    1.913mV
3.02ns    1.442mV    10.39mV    206.4uV
20ns      17.25nV    115.2nV    35.04nV
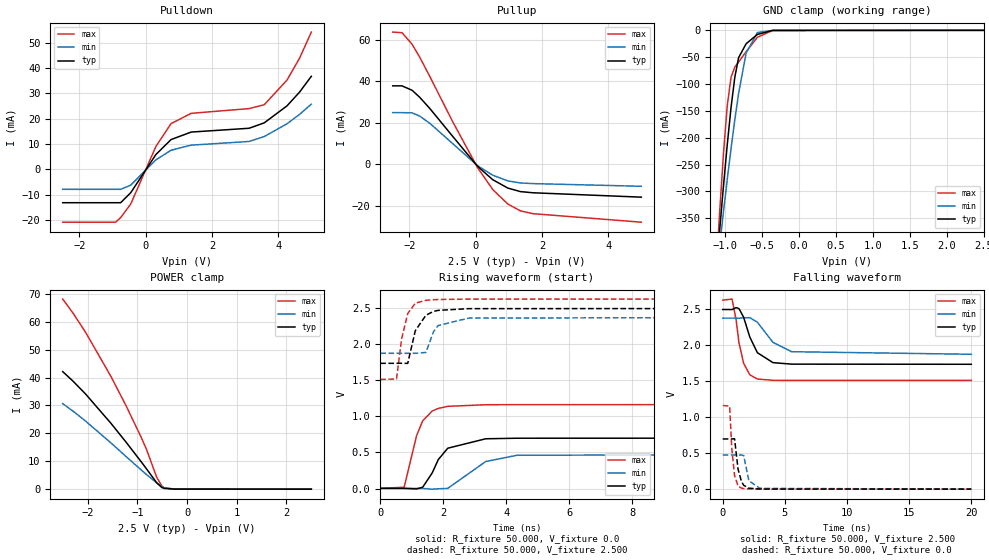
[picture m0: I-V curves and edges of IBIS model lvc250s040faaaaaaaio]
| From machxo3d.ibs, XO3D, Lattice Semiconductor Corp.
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|   Model lvc250s040faaaaaaaio
[Model] lvc250s040faaaaaaaio
Model_type I/O
Polarity   Non-Inverting
Enable   Active-Low
Vinl =  0.700V
Vinh =  1.700V
Vmeas =  1.250V
Cref =  0.0F
Rref =  1.000M
Vref =  0.0V
C_comp   4.200pF   3.800pF   7.500pF
[Temperature Range]   25.000   0.105k   -40.000
[Voltage Range]   2.500V   2.380V   2.630V
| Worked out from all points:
|   slope of the pulldown table from 0 to 0.375 V, typ, clamps not added: 54.4 ohm
|   slope of the pullup table from 0 to 0.375 V, typ, clamps not added: 65.1 ohm
|   GND clamp passes 1 mA (typ) near -0.43 V on its own axis
|   POWER clamp passes 1 mA (typ) near -0.54 V on its own axis
|   rising waveform, R_fixture 50.000, V_fixture 0.0: 20-80 % time 605ps typ, 868ps min, 437ps max; typ from 0.002 V to 0.7 V
|   rising waveform, R_fixture 50.000, V_fixture 2.500: 20-80 % time 350ps typ, 361ps min, 275ps max; typ from 1.74 V to 2.5 V
|   falling waveform, R_fixture 50.000, V_fixture 2.500: 20-80 % time 1.05ns typ, 1.59ns min, 702ps max; typ from 2.5 V to 1.74 V
|   falling waveform, R_fixture 50.000, V_fixture 0.0: 20-80 % time 360ps typ, 396ps min, 299ps max; typ from 0.7 V to 0.002 V
[Pulldown]
|Voltage   I(typ)   I(min)   I(max)
-2.5V     -13.08mA   -7.815mA   -20.75mA
-904mV    -13.08mA   -7.815mA   -20.75mA
-752mV    -13.08mA   -7.815mA   -18.92mA
-448mV    -9.14mA    -6.165mA   -13.6mA
312mV     5.902mA    3.803mA    9.102mA
768mV     11.78mA    7.58mA     18.08mA
1.376V    14.74mA    9.586mA    22.12mA
3.124V    16.24mA    11.04mA    23.98mA
3.58V     18.37mA    12.97mA    25.51mA
4.264V    25.03mA    17.97mA    35.18mA
4.644V    30.45mA    21.69mA    43.8mA
5V        36.7mA     25.73mA    54.11mA
[Pullup]
|Voltage   I(typ)   I(min)   I(max)
-2.5V     37.88mA    24.93mA    63.89mA
-2.22V    37.88mA    24.93mA    63.6mA
-1.916V   35.75mA    24.83mA    58mA
-1.688V   32.39mA    23.26mA    51.83mA
-1.384V   27mA       19.82mA    42.52mA
-700mV    13.64mA    10.08mA    20.84mA
60mV      -1.036mA   -745uA     -1.668mA
516mV     -7.495mA   -5.327mA   -12.25mA
972mV     -11.57mA   -8.084mA   -19.27mA
1.352V    -13.27mA   -9.095mA   -22.58mA
1.732V    -13.84mA   -9.404mA   -23.95mA
5V        -15.96mA   -10.7mA    -28.07mA
[GND_clamp]
|Voltage   I(typ)   I(min)   I(max)
-2.5V     -2.99A     -2.35A     -4.091A
-1.123V   -455.1mA   -463.2mA   -453.7mA
-1.072V   -370.5mA   -399.5mA   -336.3mA
-1.021V   -289.2mA   -337.4mA   -228.6mA
-970mV    -212.6mA   -277.4mA   -140mA
-919mV    -143.6mA   -220.1mA   -87.39mA
-868mV    -87.38mA   -166.5mA   -68.44mA
-817mV    -50.93mA   -117.8mA   -59.12mA
-715mV    -24.98mA   -42.36mA   -39.69mA
-562mV    -7.596mA   -4.111mA   -12.93mA
-358mV    -193.4uA   -101.2uA   -309.3uA
2.5V      13.17nA    0A         -19.29uA
[POWER_clamp]
|Voltage   I(typ)   I(min)   I(max)
-2.5V     42.14mA    30.66mA    68.15mA
-2.294V   38.75mA    27.99mA    63.15mA
-2.039V   34.09mA    24.4mA     56.2mA
-1.529V   23.59mA    16.56mA    40.38mA
-1.223V   16.79mA    11.66mA    29.8mA
-917mV    9.72mA     6.817mA    18.42mA
-815mV    7.285mA    5.246mA    14.27mA
-611mV    2.32mA     2.253mA    4.314mA
-509mV    627.1uA    959.6uA    1.202mA
-458mV    269.3uA    472.4uA    476.3uA
-254mV    28.45uA    20.72uA    43.74uA
2.5V      0A         0A         0A
[Ramp]
| variable   typ   min   max
dV/dt_r   0.419/0.610n   0.286/0.863n   0.697/0.438n
dV/dt_f   0.457/1.067n   0.302/1.573n   0.670/0.702n
R_load = 50.000
[Rising Waveform]
R_fixture= 50.000
V_fixture= 0.0
V_fixture_min= 0.0
V_fixture_max= 0.0
|time   V(typ)   V(min)   V(max)
0s        2.016mV    1.415mV    2.955mV
758ps     2.329mV    1.416mV    17.46mV
1.155ns   -5.989mV   1.888mV    736.5mV
1.349ns   18.54mV    855.8uV    940.2mV
1.648ns   215mV      -9.025mV   1.075V
1.844ns   402.1mV    -4.026mV   1.112V
2.144ns   559.5mV    2.456mV    1.141V
3.349ns   690.4mV    374.5mV    1.163V
4.345ns   698.2mV    461.6mV    1.164V
20ns      699.6mV    477.4mV    1.165V
[Rising Waveform]
R_fixture= 50.000
V_fixture= 2.500
V_fixture_min= 2.380
V_fixture_max= 2.630
|time   V(typ)   V(min)   V(max)
0s        1.738V     1.877V     1.514V
516ps     1.738V     1.877V     1.521V
678ps     1.739V     1.877V     2.079V
872ps     1.737V     1.877V     2.429V
1.114ns   2.192V     1.877V     2.573V
1.451ns   2.406V     1.889V     2.613V
1.692ns   2.459V     2.178V     2.621V
1.841ns   2.473V     2.263V     2.624V
2.816ns   2.497V     2.366V     2.63V
20ns      2.5V       2.38V      2.63V
[Falling Waveform]
R_fixture= 50.000
V_fixture= 2.500
V_fixture_min= 2.380
V_fixture_max= 2.630
|time   V(typ)   V(min)   V(max)
0s        2.5V       2.38V      2.63V
752ps     2.499V     2.38V      2.645V
1.077ns   2.526V     2.38V      2.357V
1.311ns   2.512V     2.379V     2.035V
1.681ns   2.393V     2.385V     1.753V
2.178ns   2.118V     2.386V     1.592V
2.789ns   1.899V     2.323V     1.533V
4.043ns   1.761V     2.043V     1.515V
5.539ns   1.74V      1.913V     1.514V
20ns      1.738V     1.877V     1.514V
[Falling Waveform]
R_fixture= 50.000
V_fixture= 0.0
V_fixture_min= 0.0
V_fixture_max= 0.0
|time   V(typ)   V(min)   V(max)
0s        699.6mV    477.4mV    1.165V
556ps     699.6mV    477.3mV    1.156V
733ps     699.4mV    477.4mV    559.7mV
952ps     702.5mV    477.4mV    192.5mV
1.235ns   279.4mV    477.2mV    43.11mV
1.505ns   109.8mV    477.7mV    16.66mV
1.687ns   55.64mV    468.6mV    10.54mV
2.106ns   14.99mV    117.9mV    4.785mV
2.998ns   3.575mV    12.82mV    3.138mV
20ns      2.016mV    1.415mV    2.955mV
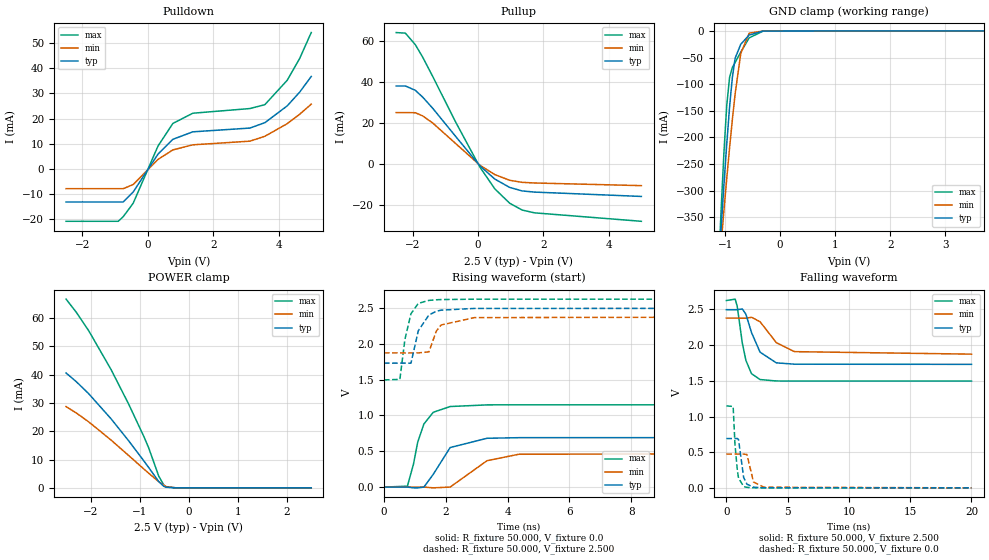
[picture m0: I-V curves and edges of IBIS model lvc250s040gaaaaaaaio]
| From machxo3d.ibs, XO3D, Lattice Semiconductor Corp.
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|   Model lvc250s040gaaaaaaaio
[Model] lvc250s040gaaaaaaaio
Model_type I/O
Polarity   Non-Inverting
Enable   Active-Low
Vinl =  0.700V
Vinh =  1.700V
Vmeas =  1.250V
Cref =  0.0F
Rref =  1.000M
Vref =  0.0V
C_comp   4.200pF   3.800pF   7.500pF
[Temperature Range]   25.000   0.105k   -40.000
[Voltage Range]   2.500V   2.380V   2.630V
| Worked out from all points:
|   slope of the pulldown table from 0 to 0.375 V, typ, clamps not added: 54.4 ohm
|   slope of the pullup table from 0 to 0.375 V, typ, clamps not added: 65.1 ohm
|   GND clamp passes 1 mA (typ) near -0.43 V on its own axis
|   POWER clamp passes 1 mA (typ) near -0.54 V on its own axis
|   rising waveform, R_fixture 50.000, V_fixture 0.0: 20-80 % time 599ps typ, 870ps min, 438ps max; typ from 0 V to 0.691 V
|   rising waveform, R_fixture 50.000, V_fixture 2.500: 20-80 % time 356ps typ, 364ps min, 278ps max; typ from 1.73 V to 2.5 V
|   falling waveform, R_fixture 50.000, V_fixture 2.500: 20-80 % time 1.07ns typ, 1.56ns min, 700ps max; typ from 2.5 V to 1.73 V
|   falling waveform, R_fixture 50.000, V_fixture 0.0: 20-80 % time 350ps typ, 387ps min, 292ps max; typ from 0.691 V to 0 V
[Pulldown]
|Voltage   I(typ)   I(min)   I(max)
-2.5V     -13.08mA   -7.815mA   -20.75mA
-904mV    -13.08mA   -7.815mA   -20.75mA
-752mV    -13.08mA   -7.815mA   -18.92mA
-448mV    -9.14mA    -6.165mA   -13.6mA
312mV     5.902mA    3.803mA    9.102mA
768mV     11.78mA    7.58mA     18.08mA
1.376V    14.74mA    9.586mA    22.12mA
3.124V    16.24mA    11.04mA    23.98mA
3.58V     18.37mA    12.97mA    25.51mA
4.264V    25.03mA    17.97mA    35.18mA
4.644V    30.45mA    21.69mA    43.8mA
5V        36.7mA     25.72mA    54.12mA
[Pullup]
|Voltage   I(typ)   I(min)   I(max)
-2.5V     37.86mA    24.9mA     63.87mA
-2.22V    37.86mA    24.9mA     63.59mA
-1.916V   35.74mA    24.82mA    57.99mA
-1.688V   32.39mA    23.26mA    51.83mA
-1.384V   27mA       19.82mA    42.52mA
-700mV    13.64mA    10.08mA    20.84mA
60mV      -1.036mA   -745uA     -1.668mA
516mV     -7.495mA   -5.327mA   -12.25mA
972mV     -11.57mA   -8.084mA   -19.27mA
1.352V    -13.27mA   -9.095mA   -22.58mA
1.732V    -13.84mA   -9.404mA   -23.95mA
5V        -15.96mA   -10.7mA    -28.07mA
[GND_clamp]
|Voltage   I(typ)   I(min)   I(max)
-2.5V     -2.99A     -2.35A     -4.091A
-1.123V   -455.1mA   -463.2mA   -453.7mA
-1.072V   -370.5mA   -399.5mA   -336.3mA
-1.021V   -289.2mA   -337.4mA   -228.6mA
-970mV    -212.6mA   -277.4mA   -140mA
-919mV    -143.6mA   -220.1mA   -87.4mA
-868mV    -87.39mA   -166.5mA   -68.45mA
-817mV    -50.94mA   -117.8mA   -59.13mA
-715mV    -24.99mA   -42.37mA   -39.7mA
-562mV    -7.608mA   -4.125mA   -12.95mA
-307mV    -97.66uA   -51.76uA   -173.8uA
5V        114uA      49.35uA    266.8uA
[POWER_clamp]
|Voltage   I(typ)   I(min)   I(max)
-2.5V     40.55mA    28.7mA     66.64mA
-2.294V   37.53mA    26.47mA    62.05mA
-2.039V   33.25mA    23.31mA    55.5mA
-1.58V    24.33mA    16.84mA    41.69mA
-1.223V   16.6mA     11.41mA    29.54mA
-917mV    9.596mA    6.709mA    18.24mA
-815mV    7.18mA     5.166mA    14.11mA
-611mV    2.243mA    2.205mA    4.167mA
-509mV    558uA      921.7uA    1.059mA
-458mV    208uA      438.7uA    350.8uA
-254mV    2.162uA    3.635uA    1.029uA
2.5V      0A         0A         0A
[Ramp]
| variable   typ   min   max
dV/dt_r   0.415/0.606n   0.284/0.862n   0.689/0.439n
dV/dt_f   0.460/1.067n   0.303/1.585n   0.677/0.700n
R_load = 50.000
[Rising Waveform]
R_fixture= 50.000
V_fixture= 0.0
V_fixture_min= 0.0
V_fixture_max= 0.0
|time   V(typ)   V(min)   V(max)
0s        9.102nV    62.88nV    33.47nV
759ps     347.9uV    2.948uV    12.62mV
956ps     -10.74mV   26.98uV    320.6mV
1.091ns   -10.78mV   240.6uV    623.9mV
1.292ns   -684uV     182.9uV    880.6mV
1.597ns   178.9mV    -10.87mV   1.045V
2.143ns   552.3mV    217.6uV    1.125V
3.338ns   681.8mV    369mV      1.148V
4.365ns   690mV      458.4mV    1.149V
20ns      691.3mV    473.6mV    1.149V
[Rising Waveform]
R_fixture= 50.000
V_fixture= 2.500
V_fixture_min= 2.380
V_fixture_max= 2.630
|time   V(typ)   V(min)   V(max)
0s        1.731V     1.874V     1.497V
516ps     1.731V     1.874V     1.504V
679ps     1.731V     1.874V     2.064V
874ps     1.73V      1.874V     2.42V
1.112ns   2.183V     1.874V     2.566V
1.455ns   2.403V     1.888V     2.607V
1.697ns   2.456V     2.18V      2.616V
1.85ns    2.471V     2.264V     2.619V
2.93ns    2.495V     2.367V     2.624V
20ns      2.497V     2.379V     2.625V
[Falling Waveform]
R_fixture= 50.000
V_fixture= 2.500
V_fixture_min= 2.380
V_fixture_max= 2.630
|time   V(typ)   V(min)   V(max)
0s        2.497V     2.379V     2.625V
721ps     2.497V     2.379V     2.645V
883ps     2.497V     2.379V     2.549V
1.304ns   2.507V     2.378V     2.029V
1.597ns   2.433V     2.378V     1.786V
2.052ns   2.178V     2.39V      1.601V
2.75ns    1.902V     2.329V     1.518V
4.078ns   1.752V     2.035V     1.498V
5.563ns   1.733V     1.909V     1.497V
20ns      1.731V     1.874V     1.497V
[Falling Waveform]
R_fixture= 50.000
V_fixture= 0.0
V_fixture_min= 0.0
V_fixture_max= 0.0
|time   V(typ)   V(min)   V(max)
0s        691.3mV    473.6mV    1.149V
556ps     691.3mV    473.5mV    1.141V
701ps     691.2mV    473.6mV    622.5mV
895ps     691.9mV    473.6mV    251.5mV
994ps     677.5mV    473.6mV    138mV
1.415ns   143.8mV    473.9mV    17.87mV
1.682ns   51.74mV    466.8mV    6.991mV
2.218ns   9.013mV    80.87mV    1.295mV
3.069ns   1.28mV     9.201mV    182.2uV
20ns      12.72nV    113.1nV    30.87nV
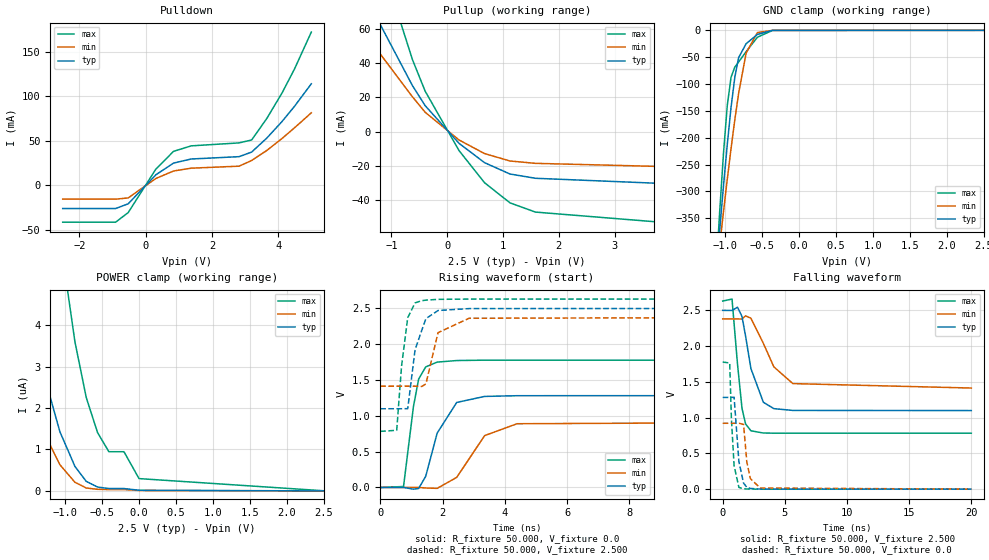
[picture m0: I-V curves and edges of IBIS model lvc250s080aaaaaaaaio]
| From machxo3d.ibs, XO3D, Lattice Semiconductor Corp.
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|   Model lvc250s080aaaaaaaaio
[Model] lvc250s080aaaaaaaaio
Model_type I/O
Polarity   Non-Inverting
Enable   Active-Low
Vinl =  0.700V
Vinh =  1.700V
Vmeas =  1.250V
Cref =  0.0F
Rref =  1.000M
Vref =  0.0V
C_comp   4.200pF   3.800pF   7.500pF
[Temperature Range]   25.000   0.105k   -40.000
[Voltage Range]   2.500V   2.380V   2.630V
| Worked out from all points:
|   slope of the pulldown table from 0 to 0.375 V, typ, clamps not added: 27.2 ohm
|   slope of the pullup table from 0 to 0.375 V, typ, clamps not added: 32.5 ohm
|   GND clamp passes 1 mA (typ) near -0.43 V on its own axis
|   rising waveform, R_fixture 50.000, V_fixture 0.0: 20-80 % time 570ps typ, 888ps min, 306ps max; typ from 0 V to 1.28 V
|   rising waveform, R_fixture 50.000, V_fixture 2.500: 20-80 % time 357ps typ, 356ps min, 253ps max; typ from 1.1 V to 2.5 V
|   falling waveform, R_fixture 50.000, V_fixture 2.500: 20-80 % time 995ps typ, 1.59ns min, 549ps max; typ from 2.5 V to 1.1 V
|   falling waveform, R_fixture 50.000, V_fixture 0.0: 20-80 % time 361ps typ, 382ps min, 280ps max; typ from 1.28 V to 0 V
[Pulldown]
|Voltage   I(typ)   I(min)   I(max)
-2.5V     -26.15mA   -15.63mA   -41.49mA
-904mV    -26.15mA   -15.63mA   -41.49mA
-524mV    -20.82mA   -14.22mA   -30.68mA
312mV     11.8mA     7.606mA    18.2mA
844mV     24.87mA    16.01mA    38.07mA
1.376V    29.47mA    19.17mA    44.23mA
2.82V     32.11mA    21.42mA    47.56mA
3.2V      37.25mA    27.79mA    50.84mA
3.656V    52.93mA    39.03mA    74.92mA
4.112V    71.39mA    52.37mA    103.3mA
4.492V    88.61mA    64.48mA    130.5mA
5V        113.9mA    81.35mA    172mA
[Pullup]
|Voltage   I(typ)   I(min)   I(max)
-2.5V     112.2mA    72.77mA    190.3mA
-2.296V   112.2mA    72.77mA    190.1mA
-2.22V    112.2mA    72.77mA    187.6mA
-1.916V   102.5mA    71.32mA    168.1mA
-1.46V    78.64mA    56.58mA    127.6mA
-624mV    26.86mA    20.33mA    42.09mA
-396mV    15.13mA    11.26mA    23.61mA
212mV     -6.926mA   -4.965mA   -11.2mA
668mV     -18.22mA   -12.89mA   -29.94mA
1.124V    -24.85mA   -17.24mA   -41.72mA
1.58V     -27.35mA   -18.62mA   -47.12mA
5V        -31.92mA   -21.41mA   -56.14mA
[GND_clamp]
|Voltage   I(typ)   I(min)   I(max)
-2.5V     -2.99A     -2.35A     -4.091A
-1.123V   -455.1mA   -463.2mA   -453.6mA
-1.072V   -370.5mA   -399.5mA   -336.3mA
-1.021V   -289.1mA   -337.4mA   -228.5mA
-970mV    -212.6mA   -277.3mA   -139.9mA
-919mV    -143.6mA   -220.1mA   -87.34mA
-868mV    -87.35mA   -166.5mA   -68.39mA
-817mV    -50.9mA    -117.8mA   -59.07mA
-715mV    -24.94mA   -42.34mA   -39.63mA
-562mV    -7.547mA   -4.077mA   -12.85mA
-358mV    -114uA     -53.77uA   -172.8uA
2.5V      0A         0A         0A
[POWER_clamp]
|Voltage   I(typ)   I(min)   I(max)
-2.5V     16.57uA    10.06uA    44.17uA
-2.09V    10.8uA     6.285uA    30.12uA
-1.682V   6.109uA    3.358uA    18.45uA
-1.376V   3.384uA    1.736uA    11.44uA
-1.07V    1.428uA    632.9nA    6.128uA
-866mV    590.6nA    207.8nA    3.594uA
-713mV    230.3nA    70.5nA     2.252uA
-560mV    93.24nA    39.01nA    1.406uA
-407mV    57.66nA    33.39nA    946nA
-203mV    57.66nA    32.38nA    946nA
1mV       16.06nA    10.58nA    297.5nA
2.5V      0A         0A         3.667nA
[Ramp]
| variable   typ   min   max
dV/dt_r   0.770/0.569n   0.553/0.881n   1.066/0.306n
dV/dt_f   0.841/1.001n   0.579/1.575n   1.108/0.551n
R_load = 50.000
[Rising Waveform]
R_fixture= 50.000
V_fixture= 0.0
V_fixture_min= 0.0
V_fixture_max= 0.0
|time   V(typ)   V(min)   V(max)
0s        6.216nV    45.16nV    21.49nV
747ps     232.8uV    -613.5nV   13.68mV
1.066ns   -23.51mV   165.6uV    1.13V
1.232ns   -14.13mV   254uV      1.513V
1.46ns    156.2mV    -7.169mV   1.683V
1.828ns   759.3mV    -12.27mV   1.75V
2.456ns   1.187V     141mV      1.772V
3.352ns   1.271V     723.8mV    1.777V
4.393ns   1.281V     889.8mV    1.777V
20ns      1.283V     921.3mV    1.777V
[Rising Waveform]
R_fixture= 50.000
V_fixture= 2.500
V_fixture_min= 2.380
V_fixture_max= 2.630
|time   V(typ)   V(min)   V(max)
0s        1.099V     1.414V     783mV
528ps     1.099V     1.414V     798.5mV
683ps     1.099V     1.414V     1.692V
882ps     1.1V       1.414V     2.37V
1.118ns   1.922V     1.414V     2.577V
1.333ns   2.194V     1.41V      2.607V
1.467ns   2.357V     1.446V     2.615V
1.855ns   2.47V      2.161V     2.626V
2.851ns   2.497V     2.362V     2.63V
20ns      2.5V       2.38V      2.63V
[Falling Waveform]
R_fixture= 50.000
V_fixture= 2.500
V_fixture_min= 2.380
V_fixture_max= 2.630
|time   V(typ)   V(min)   V(max)
0s        2.5V       2.38V      2.63V
749ps     2.499V     2.38V      2.658V
1.189ns   2.544V     2.38V      1.751V
1.553ns   2.414V     2.379V     1.129V
1.839ns   2.141V     2.423V     912.4mV
2.271ns   1.685V     2.39V      816.2mV
3.27ns    1.215V     2.038V     784.9mV
4.115ns   1.126V     1.71V      783.1mV
5.641ns   1.101V     1.476V     782.7mV
20ns      1.099V     1.414V     782.7mV
[Falling Waveform]
R_fixture= 50.000
V_fixture= 0.0
V_fixture_min= 0.0
V_fixture_max= 0.0
|time   V(typ)   V(min)   V(max)
0s        1.283V     921.3mV    1.777V
563ps     1.283V     921.2mV    1.765V
700ps     1.283V     921.3mV    984.3mV
917ps     1.285V     921.3mV    325.5mV
1.303ns   385.5mV    921.2mV    24.47mV
1.678ns   84.33mV    906.6mV    6.107mV
1.939ns   26.21mV    382mV      2.583mV
2.223ns   10.22mV    148.7mV    936.9uV
3.012ns   1.566mV    16.31mV    134.4uV
20ns      69.5nV     102.5nV    46.41nV
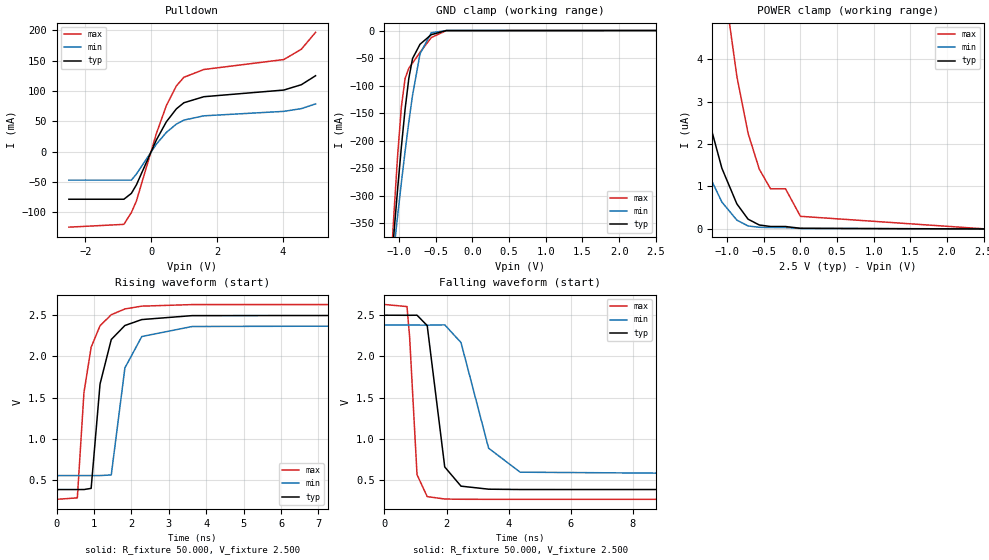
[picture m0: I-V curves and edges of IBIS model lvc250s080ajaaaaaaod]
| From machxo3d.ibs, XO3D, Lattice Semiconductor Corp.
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|   Model lvc250s080ajaaaaaaod
[Model] lvc250s080ajaaaaaaod
Model_type I/O_open_drain
Polarity   Non-Inverting
Enable   Active-Low
Vinl =  0.700V
Vinh =  1.700V
Vmeas =  1.250V
Cref =  0.0F
Rref = 10.00k
Vref = 2.50V
C_comp   4.200pF   3.800pF   7.500pF
[Temperature Range]   25.000   0.105k   -40.000
[Voltage Range]   2.500V   2.380V   2.630V
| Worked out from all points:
|   slope of the pulldown table from 0 to 0.375 V, typ, clamps not added: 9.06 ohm
|   GND clamp passes 1 mA (typ) near -0.43 V on its own axis
|   rising waveform, R_fixture 50.000, V_fixture 2.500: 20-80 % time 332ps typ, 334ps min, 338ps max; typ from 0.382 V to 2.5 V
|   falling waveform, R_fixture 50.000, V_fixture 2.500: 20-80 % time 381ps typ, 750ps min, 193ps max; typ from 2.5 V to 0.382 V
[Pulldown]
|Voltage   I(typ)   I(min)   I(max)
-2.5V     -78.46mA   -46.89mA   -124.5mA
-828mV    -78.46mA   -46.89mA   -119.9mA
-600mV    -68.8mA    -46.89mA   -100.4mA
-448mV    -54.84mA   -36.99mA   -81.59mA
160mV     19.33mA    12.46mA    29.82mA
464mV     49.32mA    31.76mA    76.03mA
768mV     70.67mA    45.48mA    108.5mA
996mV     80.71mA    52.1mA     122.7mA
1.604V    90.68mA    59.15mA    135.6mA
4.036V    101.7mA    66.53mA    152mA
4.568V    110.5mA    71.05mA    169.1mA
5V        125.3mA    78.84mA    196.9mA
[GND_clamp]
|Voltage   I(typ)   I(min)   I(max)
-2.5V     -2.99A     -2.35A     -4.091A
-1.123V   -455.1mA   -463.2mA   -453.6mA
-1.072V   -370.5mA   -399.5mA   -336.3mA
-1.021V   -289.1mA   -337.4mA   -228.5mA
-970mV    -212.6mA   -277.3mA   -139.9mA
-919mV    -143.6mA   -220.1mA   -87.34mA
-868mV    -87.35mA   -166.5mA   -68.39mA
-817mV    -50.9mA    -117.8mA   -59.07mA
-715mV    -24.94mA   -42.34mA   -39.63mA
-562mV    -7.547mA   -4.077mA   -12.85mA
-358mV    -114uA     -53.77uA   -172.8uA
2.5V      0A         0A         0A
[POWER_clamp]
|Voltage   I(typ)   I(min)   I(max)
-2.5V     16.57uA    10.06uA    44.17uA
-2.09V    10.8uA     6.285uA    30.12uA
-1.682V   6.109uA    3.358uA    18.45uA
-1.376V   3.384uA    1.736uA    11.44uA
-1.07V    1.428uA    632.9nA    6.128uA
-866mV    590.6nA    207.8nA    3.594uA
-713mV    230.3nA    70.48nA    2.252uA
-560mV    93.25nA    38.99nA    1.406uA
-407mV    57.68nA    33.38nA    946nA
-203mV    57.68nA    32.37nA    946nA
1mV       16.06nA    10.58nA    297.5nA
2.5V      0A         0A         3.667nA
[Ramp]
| variable   typ   min   max
dV/dt_r   1.271/0.333n   1.097/0.333n   1.420/0.336n
dV/dt_f   1.271/0.381n   1.097/0.750n   1.420/0.192n
R_load = 50.000
[Rising Waveform]
R_fixture= 50.000
V_fixture= 2.500
V_fixture_min= 2.380
V_fixture_max= 2.630
|time   V(typ)   V(min)   V(max)
0s        382.3mV    552.3mV    263.8mV
556ps     382.3mV    552.3mV    281.6mV
733ps     382.6mV    552.3mV    1.561V
925ps     396.7mV    552.3mV    2.111V
1.163ns   1.665V     552.3mV    2.372V
1.463ns   2.205V     559.9mV    2.506V
1.827ns   2.375V     1.86V      2.576V
2.278ns   2.447V     2.241V     2.61V
3.626ns   2.495V     2.363V     2.629V
20ns      2.5V       2.38V      2.63V
[Falling Waveform]
R_fixture= 50.000
V_fixture= 2.500
V_fixture_min= 2.380
V_fixture_max= 2.630
|time   V(typ)   V(min)   V(max)
0s        2.5V       2.38V      2.63V
725ps     2.499V     2.38V      2.605V
809ps     2.499V     2.38V      2.247V
1.049ns   2.5V       2.38V      563.8mV
1.377ns   2.374V     2.379V     296.6mV
1.941ns   656.8mV    2.383V     267.4mV
2.465ns   423.7mV    2.168V     264.3mV
3.354ns   386.8mV    884.4mV    263.7mV
4.369ns   382.8mV    593.3mV    263.7mV
20ns      382.1mV    552.3mV    263.6mV
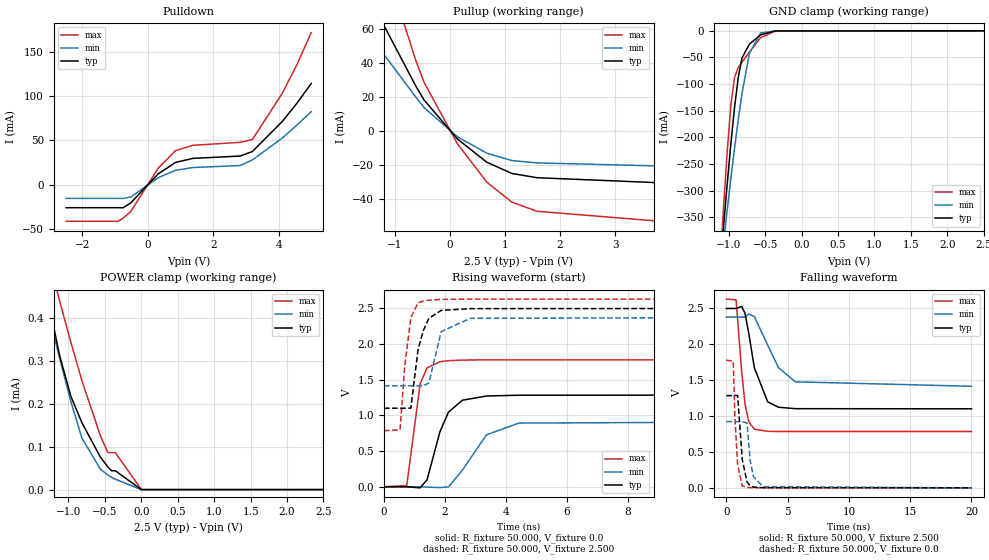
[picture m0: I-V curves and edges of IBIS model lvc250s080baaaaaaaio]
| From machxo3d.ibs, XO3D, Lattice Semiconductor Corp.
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|   Model lvc250s080baaaaaaaio
[Model] lvc250s080baaaaaaaio
Model_type I/O
Polarity   Non-Inverting
Enable   Active-Low
Vinl =  0.700V
Vinh =  1.700V
Vmeas =  1.250V
Cref =  0.0F
Rref =  1.000M
Vref =  0.0V
C_comp   4.200pF   3.800pF   7.500pF
[Temperature Range]   25.000   0.105k   -40.000
[Voltage Range]   2.500V   2.380V   2.630V
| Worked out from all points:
|   slope of the pulldown table from 0 to 0.375 V, typ, clamps not added: 27.2 ohm
|   slope of the pullup table from 0 to 0.375 V, typ, clamps not added: 32.5 ohm
|   GND clamp passes 1 mA (typ) near -0.43 V on its own axis
|   POWER clamp passes 1 mA (typ) near -1.90 V on its own axis
|   rising waveform, R_fixture 50.000, V_fixture 0.0: 20-80 % time 568ps typ, 888ps min, 306ps max; typ from 0.001 V to 1.29 V
|   rising waveform, R_fixture 50.000, V_fixture 2.500: 20-80 % time 346ps typ, 353ps min, 252ps max; typ from 1.1 V to 2.5 V
|   falling waveform, R_fixture 50.000, V_fixture 2.500: 20-80 % time 1ns typ, 1.58ns min, 552ps max; typ from 2.5 V to 1.1 V
|   falling waveform, R_fixture 50.000, V_fixture 0.0: 20-80 % time 364ps typ, 384ps min, 282ps max; typ from 1.29 V to 0.001 V
[Pulldown]
|Voltage   I(typ)   I(min)   I(max)
-2.5V     -26.15mA   -15.63mA   -41.49mA
-904mV    -26.15mA   -15.63mA   -41.49mA
-752mV    -26.15mA   -15.63mA   -37.84mA
-524mV    -20.82mA   -14.22mA   -30.68mA
312mV     11.8mA     7.606mA    18.2mA
844mV     24.87mA    16.01mA    38.07mA
1.376V    29.47mA    19.17mA    44.23mA
2.82V     32.11mA    21.41mA    47.56mA
3.2V      37.19mA    27.74mA    50.76mA
4.112V    71.05mA    52.33mA    102.8mA
4.568V    92.01mA    67.24mA    135.7mA
5V        114mA      82.19mA    171.4mA
[Pullup]
|Voltage   I(typ)   I(min)   I(max)
-2.5V     112.1mA    73mA       189.8mA
-2.296V   112.1mA    73mA       189.6mA
-2.22V    112.1mA    73mA       187.1mA
-1.916V   102.3mA    71.4mA     167.5mA
-1.46V    78.34mA    56.47mA    127.2mA
-624mV    26.82mA    20.31mA    41.99mA
-472mV    18.48mA    14mA       28.87mA
136mV     -4.568mA   -3.281mA   -7.374mA
668mV     -18.22mA   -12.89mA   -29.94mA
1.124V    -24.85mA   -17.24mA   -41.72mA
1.58V     -27.35mA   -18.62mA   -47.12mA
5V        -31.92mA   -21.41mA   -56.14mA
[GND_clamp]
|Voltage   I(typ)   I(min)   I(max)
-2.5V     -2.99A     -2.35A     -4.091A
-1.123V   -455.1mA   -463.2mA   -453.7mA
-1.072V   -370.5mA   -399.5mA   -336.3mA
-1.021V   -289.2mA   -337.4mA   -228.6mA
-970mV    -212.6mA   -277.4mA   -140mA
-919mV    -143.6mA   -220.1mA   -87.39mA
-868mV    -87.38mA   -166.5mA   -68.44mA
-817mV    -50.93mA   -117.8mA   -59.12mA
-715mV    -24.98mA   -42.36mA   -39.69mA
-562mV    -7.596mA   -4.111mA   -12.93mA
-358mV    -193.4uA   -101.2uA   -309.3uA
2.5V      13.17nA    0A         -19.29uA
[POWER_clamp]
|Voltage   I(typ)   I(min)   I(max)
-2.5V     1.538mA    1.365mA    2.125mA
-1.325V   482.6uA    450.2uA    591.5uA
-1.274V   438.4uA    413.8uA    546.6uA
-1.121V   313.5uA    307.1uA    441uA
-968mV    218.6uA    206.5uA    345.2uA
-815mV    156.3uA    120.3uA    254.8uA
-560mV    75.6uA     47.55uA    125.2uA
-458mV    52.75uA    33.88uA    86.35uA
-407mV    44.01uA    28.68uA    86.35uA
-356mV    44.01uA    24.21uA    86.35uA
1mV       0A         0A         141nA
2.5V      0A         0A         0A
[Ramp]
| variable   typ   min   max
dV/dt_r   0.771/0.569n   0.553/0.881n   1.066/0.306n
dV/dt_f   0.839/1.000n   0.578/1.585n   1.106/0.553n
R_load = 50.000
[Rising Waveform]
R_fixture= 50.000
V_fixture= 0.0
V_fixture_min= 0.0
V_fixture_max= 0.0
|time   V(typ)   V(min)   V(max)
0s        1.328mV    1.004mV    1.82mV
747ps     1.549mV    1.002mV    18.71mV
1.186ns   -13.88mV   1.254mV    1.444V
1.413ns   98.57mV    -3.594mV   1.666V
1.835ns   772.4mV    -10.08mV   1.753V
2.114ns   1.046V     -746.7uV   1.768V
2.569ns   1.214V     233.5mV    1.776V
3.361ns   1.273V     729.2mV    1.779V
4.419ns   1.284V     893.3mV    1.779V
20ns      1.286V     923.4mV    1.779V
[Rising Waveform]
R_fixture= 50.000
V_fixture= 2.500
V_fixture_min= 2.380
V_fixture_max= 2.630
|time   V(typ)   V(min)   V(max)
0s        1.102V     1.416V     786.3mV
527ps     1.102V     1.416V     800.2mV
683ps     1.102V     1.416V     1.697V
882ps     1.103V     1.416V     2.372V
1.117ns   1.922V     1.416V     2.577V
1.287ns   2.186V     1.416V     2.604V
1.473ns   2.362V     1.456V     2.615V
1.875ns   2.472V     2.175V     2.626V
2.833ns   2.497V     2.361V     2.63V
20ns      2.5V       2.38V      2.63V
[Falling Waveform]
R_fixture= 50.000
V_fixture= 2.500
V_fixture_min= 2.380
V_fixture_max= 2.630
|time   V(typ)   V(min)   V(max)
0s        2.5V       2.38V      2.63V
798ps     2.5V       2.38V      2.62V
1.246ns   2.528V     2.38V      1.63V
1.522ns   2.435V     2.379V     1.171V
1.834ns   2.149V     2.422V     919.1mV
2.288ns   1.673V     2.387V     818.1mV
3.37ns    1.2V       1.992V     788.1mV
4.257ns   1.124V     1.674V     786.5mV
5.634ns   1.104V     1.478V     786.2mV
20ns      1.102V     1.416V     786.1mV
[Falling Waveform]
R_fixture= 50.000
V_fixture= 0.0
V_fixture_min= 0.0
V_fixture_max= 0.0
|time   V(typ)   V(min)   V(max)
0s        1.286V     923.4mV    1.779V
563ps     1.286V     923.5mV    1.767V
698ps     1.286V     923.5mV    997.9mV
922ps     1.288V     923.5mV    319.5mV
1.301ns   392.3mV    923.3mV    26.84mV
1.684ns   84.83mV    903.5mV    7.747mV
1.939ns   28.23mV    384.4mV    4.29mV
2.207ns   12.44mV    158.1mV    2.897mV
3.004ns   2.988mV    18.26mV    1.936mV
20ns      1.328mV    1.004mV    1.82mV
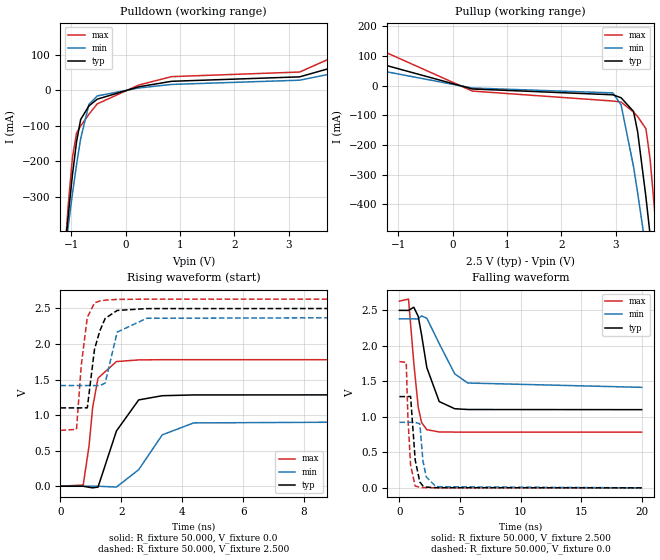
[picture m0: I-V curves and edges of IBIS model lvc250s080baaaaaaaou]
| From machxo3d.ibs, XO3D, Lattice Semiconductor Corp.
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|   Model lvc250s080baaaaaaaou
[Model] lvc250s080baaaaaaaou
Model_type Output
Polarity   Non-Inverting
Enable   Active-High
Vmeas =  1.250V
Cref =  0.0F
Rref =  1.000M
Vref =  0.0V
C_comp   4.200pF   3.800pF   7.500pF
[Temperature Range]   25.000   0.105k   -40.000
[Voltage Range]   2.500V   2.380V   2.630V
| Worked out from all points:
|   slope of the pulldown table from 0 to 0.375 V, typ, clamps not added: 27.2 ohm
|   slope of the pullup table from 0 to 0.375 V, typ, clamps not added: 32.5 ohm
|   rising waveform, R_fixture 50.000, V_fixture 0.0: 20-80 % time 568ps typ, 881ps min, 305ps max; typ from 0.001 V to 1.29 V
|   rising waveform, R_fixture 50.000, V_fixture 2.500: 20-80 % time 347ps typ, 354ps min, 252ps max; typ from 1.1 V to 2.5 V
|   falling waveform, R_fixture 50.000, V_fixture 2.500: 20-80 % time 1ns typ, 1.58ns min, 551ps max; typ from 2.5 V to 1.1 V
|   falling waveform, R_fixture 50.000, V_fixture 0.0: 20-80 % time 363ps typ, 384ps min, 282ps max; typ from 1.29 V to 0.001 V
[Pulldown]
|Voltage   I(typ)   I(min)   I(max)
-2.5V     -2.991A    -2.35A     -4.092A
-1.132V   -475mA     -476.9mA   -485.1mA
-1.056V   -351.6mA   -382.8mA   -321.6mA
-980mV    -239mA     -292.8mA   -190.2mA
-904mV    -145.4mA   -209.4mA   -121mA
-828mV    -82.59mA   -136.3mA   -101mA
-676mV    -44.45mA   -39.98mA   -67.89mA
-524mV    -25.55mA   -16.41mA   -38.81mA
236mV     9.132mA    5.891mA    14.06mA
844mV     24.79mA    15.96mA    37.92mA
3.2V      37.3mA     27.87mA    50.89mA
5V        115.6mA    83.66mA    173.3mA
[Pullup]
|Voltage   I(typ)   I(min)   I(max)
-2.5V     113.4mA    74.01mA    191.7mA
-1.992V   106.6mA    73.63mA    174.6mA
364mV     -11.26mA   -8.036mA   -18.3mA
2.948V    -30.81mA   -24.5mA    -51.86mA
3.1V      -40.87mA   -65.27mA   -55.33mA
3.328V    -86.97mA   -272.6mA   -88.94mA
3.404V    -155.7mA   -361.4mA   -104.1mA
3.556V    -375mA     -551.2mA   -145.2mA
3.632V    -500.8mA   -649.9mA   -245.9mA
3.708V    -631.5mA   -750.2mA   -403.3mA
3.784V    -765.1mA   -851.7mA   -581.6mA
5V        -3.022A    -2.541A    -3.796A
[Ramp]
| variable   typ   min   max
dV/dt_r   0.771/0.569n   0.553/0.881n   1.066/0.306n
dV/dt_f   0.839/1.000n   0.578/1.585n   1.106/0.553n
R_load = 50.000
[Rising Waveform]
R_fixture= 50.000
V_fixture= 0.0
V_fixture_min= 0.0
V_fixture_max= 0.0
|time   V(typ)   V(min)   V(max)
0s        1.328mV    1.004mV    1.82mV
747ps     1.553mV    999.3uV    18.72mV
936ps     -12.82mV   1.024mV    557.1mV
1.058ns   -21.56mV   1.093mV    1.109V
1.234ns   -10.83mV   1.25mV     1.52V
1.839ns   777.8mV    -10.22mV   1.753V
2.569ns   1.214V     233.5mV    1.776V
3.343ns   1.273V     722.8mV    1.779V
4.375ns   1.284V     891mV      1.779V
20ns      1.286V     923.4mV    1.779V
[Rising Waveform]
R_fixture= 50.000
V_fixture= 2.500
V_fixture_min= 2.380
V_fixture_max= 2.630
|time   V(typ)   V(min)   V(max)
0s        1.102V     1.416V     786.3mV
527ps     1.102V     1.416V     800.2mV
683ps     1.102V     1.416V     1.697V
882ps     1.103V     1.416V     2.372V
1.119ns   1.927V     1.416V     2.578V
1.295ns   2.186V     1.415V     2.604V
1.469ns   2.359V     1.451V     2.616V
1.863ns   2.471V     2.167V     2.626V
2.835ns   2.497V     2.361V     2.63V
20ns      2.5V       2.38V      2.63V
[Falling Waveform]
R_fixture= 50.000
V_fixture= 2.500
V_fixture_min= 2.380
V_fixture_max= 2.630
|time   V(typ)   V(min)   V(max)
0s        2.5V       2.38V      2.63V
750ps     2.499V     2.38V      2.658V
1.186ns   2.544V     2.38V      1.761V
1.55ns    2.416V     2.379V     1.137V
1.834ns   2.149V     2.422V     919.1mV
2.264ns   1.693V     2.388V     819.7mV
3.285ns   1.216V     2.032V     788.2mV
4.564ns   1.115V     1.606V     786.3mV
5.647ns   1.104V     1.477V     786.2mV
20ns      1.102V     1.416V     786.1mV
[Falling Waveform]
R_fixture= 50.000
V_fixture= 0.0
V_fixture_min= 0.0
V_fixture_max= 0.0
|time   V(typ)   V(min)   V(max)
0s        1.286V     923.4mV    1.779V
563ps     1.286V     923.4mV    1.767V
700ps     1.286V     923.5mV    989.1mV
921ps     1.288V     923.5mV    321.9mV
1.301ns   392.3mV    923.3mV    27.01mV
1.684ns   84.27mV    903.5mV    7.77mV
1.942ns   28.06mV    380mV      4.308mV
2.212ns   12.39mV    155.9mV    2.906mV
3.023ns   2.948mV    17.49mV    1.939mV
20ns      1.328mV    1.004mV    1.82mV
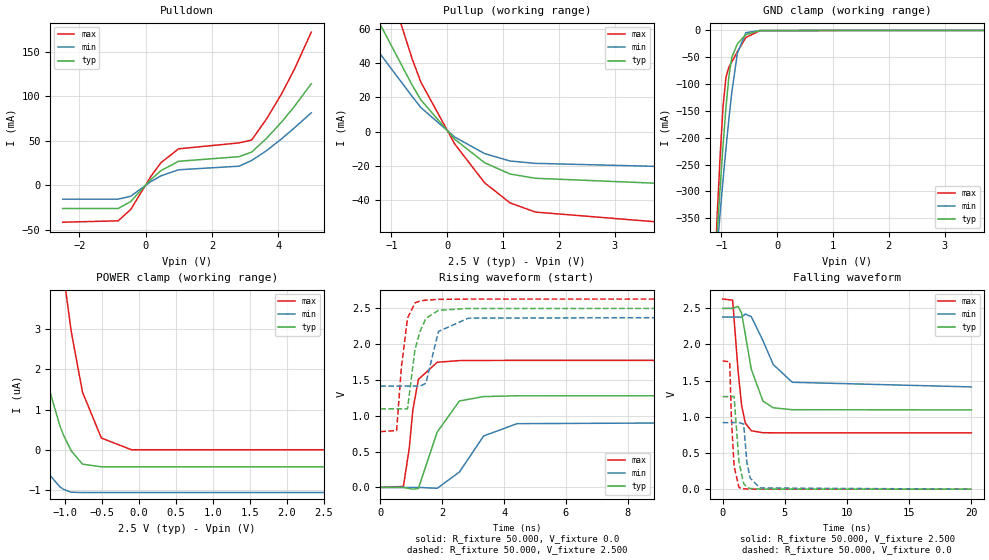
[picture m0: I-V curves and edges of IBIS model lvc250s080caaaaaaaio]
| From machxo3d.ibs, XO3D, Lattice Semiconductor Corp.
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|   Model lvc250s080caaaaaaaio
[Model] lvc250s080caaaaaaaio
Model_type I/O
Polarity   Non-Inverting
Enable   Active-Low
Vinl =  0.700V
Vinh =  1.700V
Vmeas =  1.250V
Cref =  0.0F
Rref =  1.000M
Vref =  0.0V
C_comp   4.200pF   3.800pF   7.500pF
[Temperature Range]   25.000   0.105k   -40.000
[Voltage Range]   2.500V   2.380V   2.630V
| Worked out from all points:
|   slope of the pulldown table from 0 to 0.375 V, typ, clamps not added: 27.2 ohm
|   slope of the pullup table from 0 to 0.375 V, typ, clamps not added: 32.5 ohm
|   GND clamp passes 1 mA (typ) near -0.43 V on its own axis
|   rising waveform, R_fixture 50.000, V_fixture 0.0: 20-80 % time 569ps typ, 891ps min, 308ps max; typ from 0 V to 1.28 V
|   rising waveform, R_fixture 50.000, V_fixture 2.500: 20-80 % time 350ps typ, 354ps min, 254ps max; typ from 1.1 V to 2.5 V
|   falling waveform, R_fixture 50.000, V_fixture 2.500: 20-80 % time 998ps typ, 1.59ns min, 546ps max; typ from 2.5 V to 1.09 V
|   falling waveform, R_fixture 50.000, V_fixture 0.0: 20-80 % time 356ps typ, 381ps min, 278ps max; typ from 1.28 V to 0 V
[Pulldown]
|Voltage   I(typ)   I(min)   I(max)
-2.5V     -26.15mA   -15.63mA   -41.49mA
-828mV    -26.15mA   -15.63mA   -39.97mA
-448mV    -18.28mA   -12.33mA   -27.2mA
160mV     6.444mA    4.153mA    9.94mA
464mV     16.44mA    10.59mA    25.34mA
996mV     26.9mA     17.37mA    40.9mA
2.82V     32.11mA    21.41mA    47.56mA
3.2V      37.22mA    27.79mA    50.73mA
3.656V    52.92mA    39.04mA    74.84mA
4.112V    71.4mA     52.39mA    103.2mA
4.492V    88.64mA    64.51mA    130.5mA
5V        114mA      81.4mA     172mA
[Pullup]
|Voltage   I(typ)   I(min)   I(max)
-2.5V     112.2mA    72.8mA     190.4mA
-2.296V   112.2mA    72.8mA     190.2mA
-2.22V    112.2mA    72.8mA     187.7mA
-1.916V   102.6mA    71.34mA    168.2mA
-1.46V    78.65mA    56.59mA    127.6mA
-624mV    26.83mA    20.32mA    42mA
-472mV    18.47mA    14mA       28.83mA
136mV     -4.568mA   -3.281mA   -7.374mA
668mV     -18.22mA   -12.89mA   -29.94mA
1.124V    -24.85mA   -17.24mA   -41.72mA
1.58V     -27.35mA   -18.62mA   -47.12mA
5V        -31.92mA   -21.41mA   -56.14mA
[GND_clamp]
|Voltage   I(typ)   I(min)   I(max)
-2.5V     -2.99A     -2.35A     -4.091A
-1.123V   -455.1mA   -463.2mA   -453.7mA
-1.072V   -370.5mA   -399.5mA   -336.3mA
-1.021V   -289.2mA   -337.4mA   -228.6mA
-970mV    -212.6mA   -277.4mA   -140mA
-919mV    -143.6mA   -220.1mA   -87.4mA
-868mV    -87.39mA   -166.5mA   -68.45mA
-817mV    -50.94mA   -117.8mA   -59.13mA
-715mV    -24.99mA   -42.37mA   -39.7mA
-562mV    -7.608mA   -4.125mA   -12.95mA
-307mV    -97.66uA   -51.76uA   -173.8uA
5V        114uA      49.34uA    266.8uA
[POWER_clamp]
|Voltage   I(typ)   I(min)   I(max)
-2.5V     22.27uA    8.76uA     64.97uA
-2.141V   14.03uA    4.838uA    43.67uA
-1.835V   8.45uA     2.288uA    28.47uA
-1.58V    4.901uA    736nA      18.31uA
-1.274V   1.887uA    -485.6nA   9.321uA
-1.07V    594.4nA    -923.9nA   5.173uA
-1.019V   355.1nA    -987.6nA   4.351uA
-917mV    -26.4nA    -1.058uA   2.951uA
-764mV    -358.7nA   -1.065uA   1.434uA
-509mV    -424.8nA   -1.065uA   291.6nA
-101mV    -424.8nA   -1.065uA   0A
2.5V      -424.8nA   -1.065uA   0A
[Ramp]
| variable   typ   min   max
dV/dt_r   0.768/0.570n   0.552/0.881n   1.063/0.307n
dV/dt_f   0.842/0.993n   0.580/1.592n   1.109/0.549n
R_load = 50.000
[Rising Waveform]
R_fixture= 50.000
V_fixture= 0.0
V_fixture_min= 0.0
V_fixture_max= 0.0
|time   V(typ)   V(min)   V(max)
0s        6.01nV     44.68nV    20.69nV
747ps     230.2uV    -646.2nV   13.94mV
936ps     -14.97mV   24.06uV    545.7mV
1.052ns   -24.06mV   165.4uV    1.079V
1.232ns   -13.99mV   252.4uV    1.507V
1.84ns    773mV      -11.73mV   1.746V
2.559ns   1.206V     215.9mV    1.769V
3.339ns   1.267V     717.7mV    1.771V
4.418ns   1.278V     889.5mV    1.772V
20ns      1.279V     919.6mV    1.772V
[Rising Waveform]
R_fixture= 50.000
V_fixture= 2.500
V_fixture_min= 2.380
V_fixture_max= 2.630
|time   V(typ)   V(min)   V(max)
0s        1.096V     1.413V     778.2mV
528ps     1.096V     1.413V     793.4mV
682ps     1.096V     1.413V     1.679V
881ps     1.096V     1.413V     2.361V
1.12ns    1.922V     1.413V     2.574V
1.287ns   2.18V      1.413V     2.6V
1.473ns   2.357V     1.453V     2.612V
1.879ns   2.47V      2.175V     2.623V
2.846ns   2.496V     2.361V     2.627V
20ns      2.498V     2.379V     2.627V
[Falling Waveform]
R_fixture= 50.000
V_fixture= 2.500
V_fixture_min= 2.380
V_fixture_max= 2.630
|time   V(typ)   V(min)   V(max)
0s        2.498V     2.379V     2.627V
798ps     2.498V     2.379V     2.612V
1.239ns   2.525V     2.379V     1.631V
1.519ns   2.433V     2.379V     1.159V
1.822ns   2.135V     2.42V      912.1mV
2.3ns     1.656V     2.384V     807.5mV
3.239ns   1.217V     2.052V     780.2mV
4.064ns   1.125V     1.723V     778.6mV
5.594ns   1.098V     1.477V     778.1mV
20ns      1.095V     1.413V     778.1mV
[Falling Waveform]
R_fixture= 50.000
V_fixture= 0.0
V_fixture_min= 0.0
V_fixture_max= 0.0
|time   V(typ)   V(min)   V(max)
0s        1.279V     919.6mV    1.772V
563ps     1.279V     919.5mV    1.76V
700ps     1.279V     919.7mV    975.9mV
917ps     1.282V     919.7mV    317mV
1.306ns   377.6mV    919.5mV    23.12mV
1.684ns   79.12mV    899.7mV    5.504mV
1.948ns   24.45mV    367.6mV    2.484mV
2.212ns   10.31mV    152.2mV    1.088mV
2.998ns   1.576mV    16.69mV    119.1uV
20ns      14.91nV    100.1nV    33.38nV
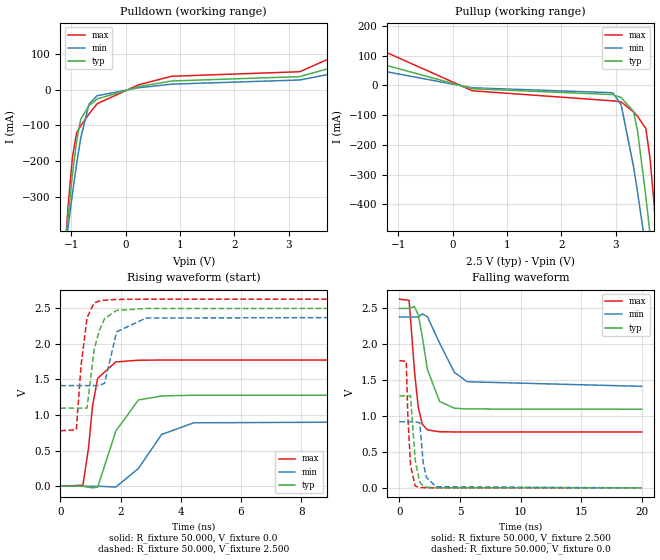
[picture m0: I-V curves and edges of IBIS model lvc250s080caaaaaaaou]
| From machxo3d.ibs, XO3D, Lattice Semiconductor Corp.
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|   Model lvc250s080caaaaaaaou
[Model] lvc250s080caaaaaaaou
Model_type Output
Polarity   Non-Inverting
Enable   Active-High
Vmeas =  1.250V
Cref =  0.0F
Rref =  1.000M
Vref =  0.0V
C_comp   4.200pF   3.800pF   7.500pF
[Temperature Range]   25.000   0.105k   -40.000
[Voltage Range]   2.500V   2.380V   2.630V
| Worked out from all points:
|   slope of the pulldown table from 0 to 0.375 V, typ, clamps not added: 27 ohm
|   slope of the pullup table from 0 to 0.375 V, typ, clamps not added: 32.5 ohm
|   rising waveform, R_fixture 50.000, V_fixture 0.0: 20-80 % time 571ps typ, 885ps min, 307ps max; typ from 0 V to 1.28 V
|   rising waveform, R_fixture 50.000, V_fixture 2.500: 20-80 % time 353ps typ, 355ps min, 254ps max; typ from 1.1 V to 2.5 V
|   falling waveform, R_fixture 50.000, V_fixture 2.500: 20-80 % time 1ns typ, 1.58ns min, 550ps max; typ from 2.5 V to 1.09 V
|   falling waveform, R_fixture 50.000, V_fixture 0.0: 20-80 % time 357ps typ, 383ps min, 278ps max; typ from 1.28 V to 0 V
[Pulldown]
|Voltage   I(typ)   I(min)   I(max)
-2.5V     -2.991A    -2.35A     -4.092A
-1.132V   -475mA     -476.9mA   -485.2mA
-1.056V   -351.6mA   -382.8mA   -321.7mA
-980mV    -239mA     -292.8mA   -190.2mA
-904mV    -145.4mA   -209.4mA   -121mA
-828mV    -82.6mA    -136.3mA   -101mA
-676mV    -44.46mA   -39.99mA   -67.9mA
-524mV    -25.56mA   -16.43mA   -38.82mA
236mV     9.262mA    5.959mA    14.32mA
844mV     24.96mA    16.05mA    38.3mA
3.2V      37.32mA    27.83mA    50.99mA
5V        114.1mA    81.46mA    172.4mA
[Pullup]
|Voltage   I(typ)   I(min)   I(max)
-2.5V     112.4mA    72.85mA    190.7mA
-1.992V   105.9mA    72.61mA    174.2mA
364mV     -11.13mA   -7.978mA   -18.01mA
2.948V    -30.82mA   -24.51mA   -51.85mA
3.1V      -40.88mA   -65.28mA   -55.33mA
3.328V    -86.97mA   -272.6mA   -88.95mA
3.404V    -155.7mA   -361.4mA   -104.1mA
3.556V    -375mA     -551.2mA   -145.3mA
3.632V    -500.8mA   -649.9mA   -245.9mA
3.708V    -631.5mA   -750.2mA   -403.3mA
3.784V    -765.1mA   -851.7mA   -581.6mA
5V        -3.022A    -2.541A    -3.796A
[Ramp]
| variable   typ   min   max
dV/dt_r   0.768/0.570n   0.552/0.881n   1.063/0.307n
dV/dt_f   0.842/0.993n   0.580/1.592n   1.109/0.549n
R_load = 50.000
[Rising Waveform]
R_fixture= 50.000
V_fixture= 0.0
V_fixture_min= 0.0
V_fixture_max= 0.0
|time   V(typ)   V(min)   V(max)
0s        6.01nV     44.68nV    20.69nV
747ps     218.5uV    -3.59uV    13.95mV
936ps     -14.66mV   21.37uV    545.7mV
1.066ns   -23.3mV    226.6uV    1.125V
1.238ns   -13.4mV    -19.35uV   1.515V
1.84ns    773mV      -11.89mV   1.745V
2.59ns    1.211V     247.8mV    1.769V
3.363ns   1.267V     726.3mV    1.772V
4.429ns   1.278V     890mV      1.772V
20ns      1.279V     919.6mV    1.772V
[Rising Waveform]
R_fixture= 50.000
V_fixture= 2.500
V_fixture_min= 2.380
V_fixture_max= 2.630
|time   V(typ)   V(min)   V(max)
0s        1.096V     1.413V     778.2mV
528ps     1.096V     1.413V     793.4mV
683ps     1.096V     1.413V     1.683V
883ps     1.097V     1.413V     2.365V
1.117ns   1.915V     1.413V     2.573V
1.284ns   2.177V     1.413V     2.6V
1.469ns   2.355V     1.447V     2.612V
1.867ns   2.469V     2.167V     2.623V
2.846ns   2.495V     2.361V     2.626V
20ns      2.498V     2.379V     2.627V
[Falling Waveform]
R_fixture= 50.000
V_fixture= 2.500
V_fixture_min= 2.380
V_fixture_max= 2.630
|time   V(typ)   V(min)   V(max)
0s        2.498V     2.379V     2.627V
800ps     2.498V     2.379V     2.61V
1.239ns   2.525V     2.379V     1.631V
1.555ns   2.408V     2.378V     1.117V
1.882ns   2.114V     2.421V     887mV
2.309ns   1.649V     2.383V     807.1mV
3.317ns   1.202V     2.014V     780.5mV
4.54ns    1.109V     1.607V     778.3mV
5.602ns   1.098V     1.477V     778.2mV
20ns      1.095V     1.413V     778.2mV
[Falling Waveform]
R_fixture= 50.000
V_fixture= 0.0
V_fixture_min= 0.0
V_fixture_max= 0.0
|time   V(typ)   V(min)   V(max)
0s        1.279V     919.6mV    1.772V
563ps     1.279V     919.7mV    1.76V
700ps     1.279V     919.7mV    975.9mV
919ps     1.282V     919.7mV    312.1mV
1.3ns     385.4mV    919.5mV    24.13mV
1.678ns   81.79mV    904.9mV    5.898mV
1.954ns   24.21mV    359.4mV    2.449mV
2.228ns   10.07mV    145.2mV    1.018mV
3.018ns   1.492mV    15.89mV    164.6uV
20ns      62.01nV    101.2nV    38.47nV
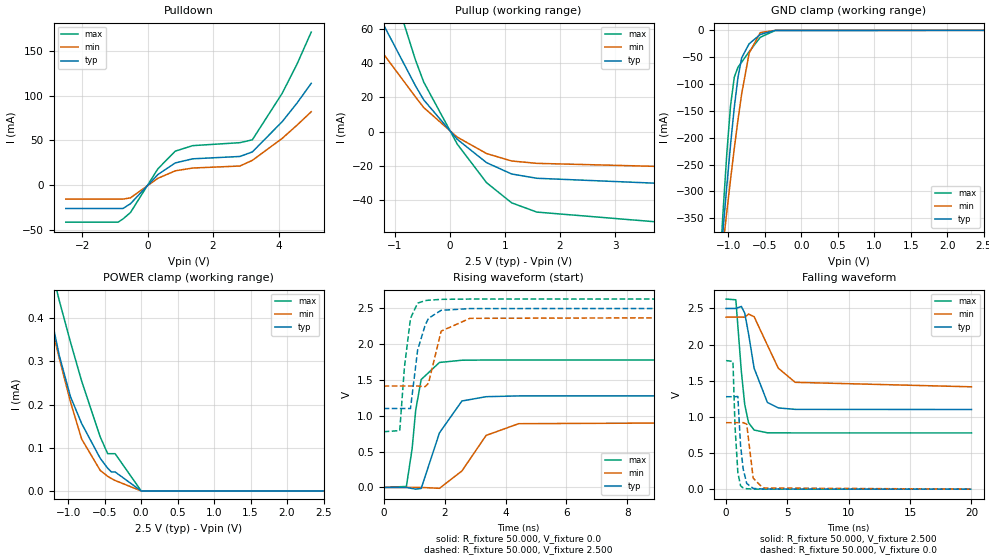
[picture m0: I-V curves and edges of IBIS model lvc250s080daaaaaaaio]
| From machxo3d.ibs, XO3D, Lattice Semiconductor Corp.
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|   Model lvc250s080daaaaaaaio
[Model] lvc250s080daaaaaaaio
Model_type I/O
Polarity   Non-Inverting
Enable   Active-Low
Vinl =  0.700V
Vinh =  1.700V
Vmeas =  1.250V
Cref =  0.0F
Rref =  1.000M
Vref =  0.0V
C_comp   4.200pF   3.800pF   7.500pF
[Temperature Range]   25.000   0.105k   -40.000
[Voltage Range]   2.500V   2.380V   2.630V
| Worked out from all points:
|   slope of the pulldown table from 0 to 0.375 V, typ, clamps not added: 27.2 ohm
|   slope of the pullup table from 0 to 0.375 V, typ, clamps not added: 32.5 ohm
|   GND clamp passes 1 mA (typ) near -0.43 V on its own axis
|   POWER clamp passes 1 mA (typ) near -1.90 V on its own axis
|   rising waveform, R_fixture 50.000, V_fixture 0.0: 20-80 % time 570ps typ, 888ps min, 311ps max; typ from 0 V to 1.28 V
|   rising waveform, R_fixture 50.000, V_fixture 2.500: 20-80 % time 346ps typ, 352ps min, 254ps max; typ from 1.1 V to 2.5 V
|   falling waveform, R_fixture 50.000, V_fixture 2.500: 20-80 % time 1.01ns typ, 1.57ns min, 557ps max; typ from 2.5 V to 1.1 V
|   falling waveform, R_fixture 50.000, V_fixture 0.0: 20-80 % time 357ps typ, 383ps min, 283ps max; typ from 1.28 V to 0 V
[Pulldown]
|Voltage   I(typ)   I(min)   I(max)
-2.5V     -26.15mA   -15.63mA   -41.49mA
-904mV    -26.15mA   -15.63mA   -41.49mA
-752mV    -26.15mA   -15.63mA   -37.84mA
-524mV    -20.82mA   -14.22mA   -30.68mA
312mV     11.8mA     7.606mA    18.2mA
844mV     24.87mA    16.01mA    38.07mA
1.376V    29.47mA    19.17mA    44.23mA
2.82V     32.11mA    21.41mA    47.56mA
3.2V      37.19mA    27.74mA    50.76mA
4.112V    71.05mA    52.33mA    102.8mA
4.568V    92.01mA    67.24mA    135.7mA
5V        114mA      82.19mA    171.4mA
[Pullup]
|Voltage   I(typ)   I(min)   I(max)
-2.5V     112.1mA    73mA       189.8mA
-2.296V   112.1mA    73mA       189.6mA
-2.22V    112.1mA    73mA       187.1mA
-1.916V   102.3mA    71.4mA     167.5mA
-1.46V    78.34mA    56.47mA    127.2mA
-624mV    26.82mA    20.31mA    41.99mA
-472mV    18.48mA    14mA       28.87mA
136mV     -4.568mA   -3.281mA   -7.374mA
668mV     -18.22mA   -12.89mA   -29.94mA
1.124V    -24.85mA   -17.24mA   -41.72mA
1.58V     -27.35mA   -18.62mA   -47.12mA
5V        -31.92mA   -21.41mA   -56.14mA
[GND_clamp]
|Voltage   I(typ)   I(min)   I(max)
-2.5V     -2.99A     -2.35A     -4.091A
-1.123V   -455.1mA   -463.2mA   -453.7mA
-1.072V   -370.5mA   -399.5mA   -336.3mA
-1.021V   -289.2mA   -337.4mA   -228.6mA
-970mV    -212.6mA   -277.4mA   -140mA
-919mV    -143.6mA   -220.1mA   -87.4mA
-868mV    -87.39mA   -166.5mA   -68.45mA
-817mV    -50.94mA   -117.8mA   -59.13mA
-715mV    -24.99mA   -42.37mA   -39.7mA
-562mV    -7.608mA   -4.125mA   -12.95mA
-358mV    -194.9uA   -98.36uA   -303.6uA
2.5V      13.17nA    0A         -19.29uA
[POWER_clamp]
|Voltage   I(typ)   I(min)   I(max)
-2.5V     1.538mA    1.365mA    2.125mA
-1.325V   482.6uA    450.2uA    591.5uA
-1.274V   438.4uA    413.8uA    546.6uA
-1.121V   313.5uA    307.1uA    441uA
-968mV    218.6uA    206.5uA    345.2uA
-815mV    156.3uA    120.3uA    254.8uA
-560mV    75.6uA     47.55uA    125.2uA
-458mV    52.75uA    33.88uA    86.35uA
-407mV    44.01uA    28.68uA    86.35uA
-356mV    44.01uA    24.21uA    86.35uA
1mV       0A         0A         141nA
2.5V      0A         0A         0A
[Ramp]
| variable   typ   min   max
dV/dt_r   0.768/0.570n   0.552/0.881n   1.068/0.310n
dV/dt_f   0.839/1.000n   0.578/1.585n   1.111/0.558n
R_load = 50.000
[Rising Waveform]
R_fixture= 50.000
V_fixture= 0.0
V_fixture_min= 0.0
V_fixture_max= 0.0
|time   V(typ)   V(min)   V(max)
0s        6.01nV     44.68nV    20.69nV
747ps     230.2uV    -669.7nV   13.94mV
936ps     -14.97mV   24.06uV    545.7mV
1.052ns   -24.06mV   165.4uV    1.079V
1.232ns   -13.99mV   252.4uV    1.507V
1.832ns   762.4mV    -12.21mV   1.745V
2.569ns   1.207V     230.1mV    1.776V
3.363ns   1.267V     726.3mV    1.779V
4.431ns   1.278V     890.2mV    1.779V
20ns      1.279V     919.6mV    1.779V
[Rising Waveform]
R_fixture= 50.000
V_fixture= 2.500
V_fixture_min= 2.380
V_fixture_max= 2.630
|time   V(typ)   V(min)   V(max)
0s        1.102V     1.416V     778.2mV
528ps     1.102V     1.416V     793.4mV
682ps     1.102V     1.416V     1.679V
881ps     1.102V     1.416V     2.361V
1.115ns   1.917V     1.416V     2.573V
1.362ns   2.266V     1.407V     2.608V
1.473ns   2.362V     1.456V     2.614V
1.887ns   2.473V     2.182V     2.626V
2.833ns   2.497V     2.361V     2.63V
20ns      2.5V       2.38V      2.63V
[Falling Waveform]
R_fixture= 50.000
V_fixture= 2.500
V_fixture_min= 2.380
V_fixture_max= 2.630
|time   V(typ)   V(min)   V(max)
0s        2.5V       2.38V      2.63V
798ps     2.5V       2.38V      2.62V
1.246ns   2.528V     2.38V      1.63V
1.522ns   2.435V     2.379V     1.171V
1.834ns   2.149V     2.422V     919.1mV
2.288ns   1.673V     2.386V     818.1mV
3.37ns    1.2V       1.992V     780.2mV
4.257ns   1.124V     1.674V     778.6mV
5.634ns   1.104V     1.478V     778.2mV
20ns      1.102V     1.416V     778.1mV
[Falling Waveform]
R_fixture= 50.000
V_fixture= 0.0
V_fixture_min= 0.0
V_fixture_max= 0.0
|time   V(typ)   V(min)   V(max)
0s        1.279V     919.6mV    1.779V
563ps     1.279V     919.5mV    1.767V
729ps     1.279V     919.7mV    873mV
962ps     1.282V     919.7mV    231.3mV
1.179ns   612.2mV    919.6mV    47.74mV
1.39ns    284.1mV    920.2mV    18.28mV
1.684ns   79.12mV    899.7mV    6.412mV
2.212ns   10.31mV    152.2mV    1.055mV
2.998ns   1.576mV    16.69mV    176.5uV
20ns      14.91nV    100.1nV    30.41nV
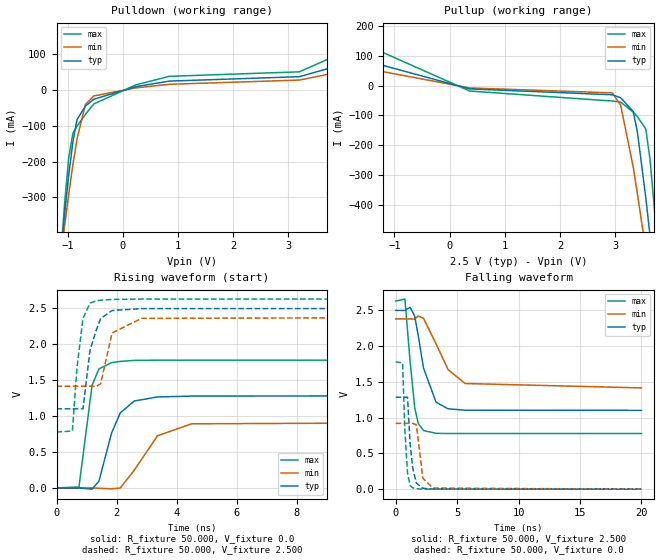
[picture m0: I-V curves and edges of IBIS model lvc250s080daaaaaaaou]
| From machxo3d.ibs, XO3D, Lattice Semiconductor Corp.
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|   Model lvc250s080daaaaaaaou
[Model] lvc250s080daaaaaaaou
Model_type Output
Polarity   Non-Inverting
Enable   Active-High
Vmeas =  1.250V
Cref =  0.0F
Rref =  1.000M
Vref =  0.0V
C_comp   4.200pF   3.800pF   7.500pF
[Temperature Range]   25.000   0.105k   -40.000
[Voltage Range]   2.500V   2.380V   2.630V
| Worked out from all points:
|   slope of the pulldown table from 0 to 0.375 V, typ, clamps not added: 27 ohm
|   slope of the pullup table from 0 to 0.375 V, typ, clamps not added: 32.5 ohm
|   rising waveform, R_fixture 50.000, V_fixture 0.0: 20-80 % time 576ps typ, 884ps min, 310ps max; typ from 0 V to 1.29 V
|   rising waveform, R_fixture 50.000, V_fixture 2.500: 20-80 % time 347ps typ, 356ps min, 255ps max; typ from 1.1 V to 2.5 V
|   falling waveform, R_fixture 50.000, V_fixture 2.500: 20-80 % time 1ns typ, 1.58ns min, 555ps max; typ from 2.5 V to 1.1 V
|   falling waveform, R_fixture 50.000, V_fixture 0.0: 20-80 % time 365ps typ, 381ps min, 283ps max; typ from 1.29 V to 0 V
[Pulldown]
|Voltage   I(typ)   I(min)   I(max)
-2.5V     -2.991A    -2.35A     -4.092A
-1.132V   -475mA     -476.9mA   -485.2mA
-1.056V   -351.6mA   -382.8mA   -321.7mA
-980mV    -239mA     -292.8mA   -190.2mA
-904mV    -145.4mA   -209.4mA   -121mA
-828mV    -82.6mA    -136.3mA   -101mA
-676mV    -44.46mA   -39.99mA   -67.9mA
-524mV    -25.56mA   -16.43mA   -38.82mA
236mV     9.262mA    5.959mA    14.32mA
844mV     24.96mA    16.05mA    38.3mA
3.2V      37.3mA     27.87mA    50.89mA
5V        115.6mA    83.66mA    173.3mA
[Pullup]
|Voltage   I(typ)   I(min)   I(max)
-2.5V     113.4mA    74.01mA    191.7mA
-1.992V   106.6mA    73.63mA    174.6mA
364mV     -11.26mA   -8.036mA   -18.3mA
2.948V    -30.82mA   -24.51mA   -51.85mA
3.1V      -40.88mA   -65.28mA   -55.33mA
3.328V    -86.97mA   -272.6mA   -88.95mA
3.404V    -155.7mA   -361.4mA   -104.1mA
3.556V    -375mA     -551.2mA   -145.3mA
3.632V    -500.8mA   -649.9mA   -245.9mA
3.708V    -631.5mA   -750.2mA   -403.3mA
3.784V    -765.1mA   -851.7mA   -581.6mA
5V        -3.022A    -2.541A    -3.796A
[Ramp]
| variable   typ   min   max
dV/dt_r   0.771/0.577n   0.552/0.881n   1.068/0.310n
dV/dt_f   0.839/1.000n   0.578/1.585n   1.111/0.558n
R_load = 50.000
[Rising Waveform]
R_fixture= 50.000
V_fixture= 0.0
V_fixture_min= 0.0
V_fixture_max= 0.0
|time   V(typ)   V(min)   V(max)
0s        6.01nV     44.68nV    20.69nV
747ps     218.5uV    -3.613uV   13.95mV
1.184ns   -16.75mV   248.5uV    1.429V
1.413ns   95.04mV    -4.275mV   1.658V
1.836ns   767.7mV    -11.83mV   1.745V
2.123ns   1.044V     -1.725mV   1.762V
2.59ns    1.211V     247.8mV    1.776V
3.363ns   1.267V     726.3mV    1.779V
4.503ns   1.279V     893.5mV    1.779V
20ns      1.286V     919.6mV    1.779V
[Rising Waveform]
R_fixture= 50.000
V_fixture= 2.500
V_fixture_min= 2.380
V_fixture_max= 2.630
|time   V(typ)   V(min)   V(max)
0s        1.102V     1.416V     778.2mV
528ps     1.102V     1.416V     793.4mV
682ps     1.102V     1.416V     1.679V
881ps     1.102V     1.416V     2.361V
1.117ns   1.922V     1.416V     2.573V
1.323ns   2.196V     1.413V     2.605V
1.469ns   2.359V     1.451V     2.614V
1.851ns   2.47V      2.158V     2.625V
2.833ns   2.497V     2.361V     2.63V
20ns      2.5V       2.38V      2.63V
[Falling Waveform]
R_fixture= 50.000
V_fixture= 2.500
V_fixture_min= 2.380
V_fixture_max= 2.630
|time   V(typ)   V(min)   V(max)
0s        2.5V       2.38V      2.63V
750ps     2.499V     2.38V      2.658V
1.186ns   2.544V     2.38V      1.761V
1.55ns    2.416V     2.379V     1.137V
1.834ns   2.149V     2.422V     919.1mV
2.264ns   1.693V     2.388V     819.7mV
3.285ns   1.216V     2.032V     780.4mV
4.26ns    1.124V     1.673V     778.4mV
5.647ns   1.104V     1.477V     778.2mV
20ns      1.102V     1.416V     778.2mV
[Falling Waveform]
R_fixture= 50.000
V_fixture= 0.0
V_fixture_min= 0.0
V_fixture_max= 0.0
|time   V(typ)   V(min)   V(max)
0s        1.286V     919.6mV    1.779V
563ps     1.286V     919.7mV    1.767V
731ps     1.285V     919.7mV    865.8mV
963ps     1.287V     919.7mV    229.4mV
1.177ns   625.4mV    919.6mV    47.98mV
1.384ns   297.7mV    920.2mV    19.13mV
1.684ns   84.27mV    899.7mV    6.584mV
2.212ns   12.23mV    152.2mV    1.117mV
3.037ns   1.81mV     15.15mV    126.5uV
20ns      62.21nV    101.2nV    39.57nV
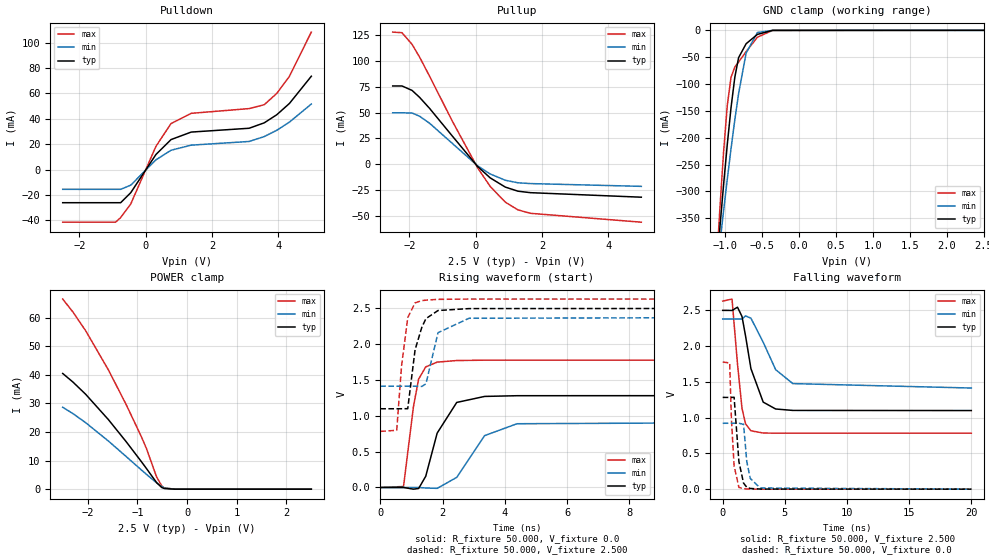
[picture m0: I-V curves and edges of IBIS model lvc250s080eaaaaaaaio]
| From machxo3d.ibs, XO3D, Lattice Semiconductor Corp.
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|   Model lvc250s080eaaaaaaaio
[Model] lvc250s080eaaaaaaaio
Model_type I/O
Polarity   Non-Inverting
Enable   Active-Low
Vinl =  0.700V
Vinh =  1.700V
Vmeas =  1.250V
Cref =  0.0F
Rref =  1.000M
Vref =  0.0V
C_comp   4.200pF   3.800pF   7.500pF
[Temperature Range]   25.000   0.105k   -40.000
[Voltage Range]   2.500V   2.380V   2.630V
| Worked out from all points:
|   slope of the pulldown table from 0 to 0.375 V, typ, clamps not added: 27.2 ohm
|   slope of the pullup table from 0 to 0.375 V, typ, clamps not added: 32.5 ohm
|   GND clamp passes 1 mA (typ) near -0.43 V on its own axis
|   POWER clamp passes 1 mA (typ) near -0.54 V on its own axis
|   rising waveform, R_fixture 50.000, V_fixture 0.0: 20-80 % time 570ps typ, 888ps min, 306ps max; typ from 0 V to 1.28 V
|   rising waveform, R_fixture 50.000, V_fixture 2.500: 20-80 % time 357ps typ, 356ps min, 253ps max; typ from 1.1 V to 2.5 V
|   falling waveform, R_fixture 50.000, V_fixture 2.500: 20-80 % time 996ps typ, 1.58ns min, 549ps max; typ from 2.5 V to 1.1 V
|   falling waveform, R_fixture 50.000, V_fixture 0.0: 20-80 % time 361ps typ, 382ps min, 280ps max; typ from 1.28 V to 0 V
[Pulldown]
|Voltage   I(typ)   I(min)   I(max)
-2.5V     -26.15mA   -15.63mA   -41.49mA
-904mV    -26.15mA   -15.63mA   -41.49mA
-752mV    -26.15mA   -15.63mA   -37.84mA
-448mV    -18.28mA   -12.33mA   -27.2mA
312mV     11.8mA     7.606mA    18.2mA
768mV     23.56mA    15.16mA    36.16mA
1.376V    29.47mA    19.17mA    44.23mA
3.124V    32.48mA    22.07mA    47.96mA
3.58V     36.75mA    25.93mA    51.02mA
3.96V     43.16mA    30.92mA    59.98mA
4.34V     52.02mA    37.33mA    73.41mA
5V        73.43mA    51.54mA    108.2mA
[Pullup]
|Voltage   I(typ)   I(min)   I(max)
-2.5V     75.89mA    49.88mA    128.1mA
-2.22V    75.89mA    49.88mA    127.5mA
-1.916V   71.57mA    49.69mA    116.2mA
-1.688V   64.82mA    46.54mA    103.8mA
-1.384V   54.02mA    39.65mA    85.08mA
-700mV    27.27mA    20.17mA    41.68mA
60mV      -2.071mA   -1.49mA    -3.336mA
440mV     -13.18mA   -9.386mA   -21.47mA
896mV     -22.1mA    -15.49mA   -36.68mA
1.276V    -26.08mA   -17.95mA   -44.18mA
1.656V    -27.53mA   -18.72mA   -47.54mA
5V        -31.92mA   -21.41mA   -56.14mA
[GND_clamp]
|Voltage   I(typ)   I(min)   I(max)
-2.5V     -2.99A     -2.35A     -4.091A
-1.123V   -455.1mA   -463.2mA   -453.6mA
-1.072V   -370.5mA   -399.5mA   -336.3mA
-1.021V   -289.1mA   -337.4mA   -228.5mA
-970mV    -212.6mA   -277.3mA   -139.9mA
-919mV    -143.6mA   -220.1mA   -87.34mA
-868mV    -87.35mA   -166.5mA   -68.39mA
-817mV    -50.9mA    -117.8mA   -59.07mA
-715mV    -24.94mA   -42.34mA   -39.63mA
-562mV    -7.547mA   -4.077mA   -12.85mA
-358mV    -114uA     -53.77uA   -172.8uA
2.5V      0A         0A         0A
[POWER_clamp]
|Voltage   I(typ)   I(min)   I(max)
-2.5V     40.49mA    28.66mA    66.53mA
-2.294V   37.48mA    26.44mA    61.99mA
-2.039V   33.22mA    23.28mA    55.47mA
-1.58V    24.32mA    16.83mA    41.7mA
-1.223V   16.6mA     11.41mA    29.58mA
-917mV    9.616mA    6.712mA    18.32mA
-815mV    7.205mA    5.171mA    14.19mA
-611mV    2.275mA    2.213mA    4.254mA
-509mV    589.4uA    929.1uA    1.152mA
-458mV    232.9uA    445.2uA    427.7uA
-254mV    3.785uA    4.472uA    4.114uA
2.5V      0A         0A         3.667nA
[Ramp]
| variable   typ   min   max
dV/dt_r   0.770/0.569n   0.553/0.881n   1.066/0.306n
dV/dt_f   0.841/1.001n   0.579/1.575n   1.108/0.551n
R_load = 50.000
[Rising Waveform]
R_fixture= 50.000
V_fixture= 0.0
V_fixture_min= 0.0
V_fixture_max= 0.0
|time   V(typ)   V(min)   V(max)
0s        6.216nV    45.16nV    21.49nV
747ps     232.8uV    -613.5nV   13.68mV
1.066ns   -23.51mV   165.6uV    1.13V
1.232ns   -14.13mV   254uV      1.513V
1.46ns    156.2mV    -7.169mV   1.683V
1.828ns   759.3mV    -12.27mV   1.75V
2.456ns   1.187V     141mV      1.772V
3.352ns   1.271V     723.8mV    1.777V
4.393ns   1.281V     889.8mV    1.777V
20ns      1.283V     921.3mV    1.777V
[Rising Waveform]
R_fixture= 50.000
V_fixture= 2.500
V_fixture_min= 2.380
V_fixture_max= 2.630
|time   V(typ)   V(min)   V(max)
0s        1.099V     1.414V     783mV
528ps     1.099V     1.414V     798.5mV
683ps     1.099V     1.414V     1.692V
882ps     1.1V       1.414V     2.37V
1.118ns   1.922V     1.414V     2.577V
1.334ns   2.235V     1.41V      2.608V
1.467ns   2.357V     1.446V     2.615V
1.855ns   2.47V      2.161V     2.626V
2.851ns   2.497V     2.362V     2.63V
20ns      2.5V       2.38V      2.63V
[Falling Waveform]
R_fixture= 50.000
V_fixture= 2.500
V_fixture_min= 2.380
V_fixture_max= 2.630
|time   V(typ)   V(min)   V(max)
0s        2.5V       2.38V      2.63V
749ps     2.499V     2.38V      2.658V
1.189ns   2.544V     2.38V      1.751V
1.553ns   2.414V     2.379V     1.129V
1.839ns   2.141V     2.423V     912.4mV
2.271ns   1.685V     2.39V      816.2mV
3.258ns   1.217V     2.054V     784.9mV
4.26ns    1.121V     1.671V     783mV
5.641ns   1.101V     1.476V     782.7mV
20ns      1.099V     1.414V     782.7mV
[Falling Waveform]
R_fixture= 50.000
V_fixture= 0.0
V_fixture_min= 0.0
V_fixture_max= 0.0
|time   V(typ)   V(min)   V(max)
0s        1.283V     921.3mV    1.777V
563ps     1.283V     921.2mV    1.765V
700ps     1.283V     921.3mV    984.3mV
917ps     1.285V     921.3mV    325.5mV
1.303ns   385.5mV    921.2mV    24.47mV
1.678ns   84.33mV    906.6mV    6.107mV
1.939ns   26.21mV    382mV      2.583mV
2.223ns   10.22mV    148.7mV    936.9uV
3.012ns   1.563mV    16.31mV    134.4uV
20ns      69.5nV     102.5nV    46.41nV
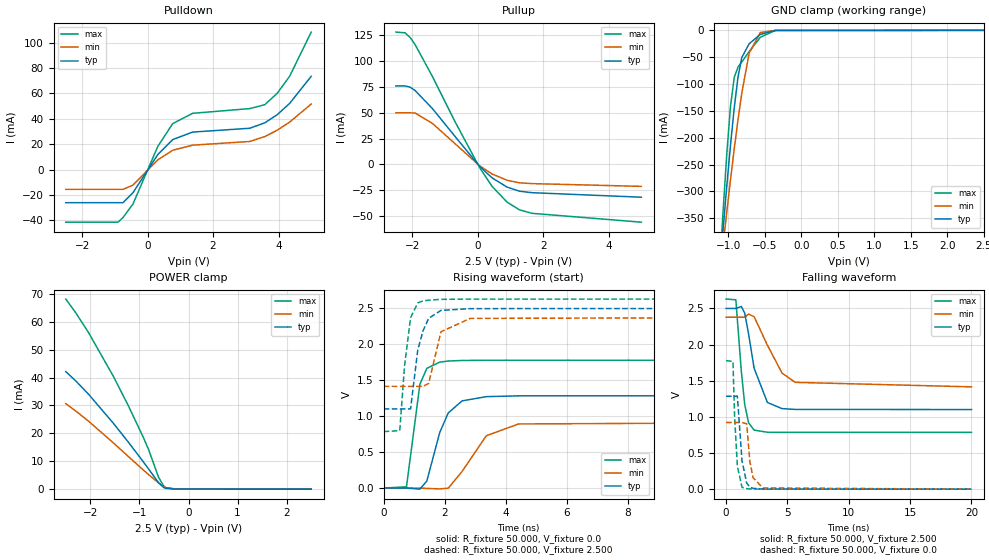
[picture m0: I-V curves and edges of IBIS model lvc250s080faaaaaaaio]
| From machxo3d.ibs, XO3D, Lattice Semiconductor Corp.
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|   Model lvc250s080faaaaaaaio
[Model] lvc250s080faaaaaaaio
Model_type I/O
Polarity   Non-Inverting
Enable   Active-Low
Vinl =  0.700V
Vinh =  1.700V
Vmeas =  1.250V
Cref =  0.0F
Rref =  1.000M
Vref =  0.0V
C_comp   4.200pF   3.800pF   7.500pF
[Temperature Range]   25.000   0.105k   -40.000
[Voltage Range]   2.500V   2.380V   2.630V
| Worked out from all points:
|   slope of the pulldown table from 0 to 0.375 V, typ, clamps not added: 27.2 ohm
|   slope of the pullup table from 0 to 0.375 V, typ, clamps not added: 32.5 ohm
|   GND clamp passes 1 mA (typ) near -0.43 V on its own axis
|   POWER clamp passes 1 mA (typ) near -0.54 V on its own axis
|   rising waveform, R_fixture 50.000, V_fixture 0.0: 20-80 % time 568ps typ, 888ps min, 306ps max; typ from 0.001 V to 1.29 V
|   rising waveform, R_fixture 50.000, V_fixture 2.500: 20-80 % time 346ps typ, 353ps min, 252ps max; typ from 1.1 V to 2.5 V
|   falling waveform, R_fixture 50.000, V_fixture 2.500: 20-80 % time 1ns typ, 1.59ns min, 552ps max; typ from 2.5 V to 1.1 V
|   falling waveform, R_fixture 50.000, V_fixture 0.0: 20-80 % time 364ps typ, 384ps min, 282ps max; typ from 1.29 V to 0.001 V
[Pulldown]
|Voltage   I(typ)   I(min)   I(max)
-2.5V     -26.15mA   -15.63mA   -41.49mA
-904mV    -26.15mA   -15.63mA   -41.49mA
-752mV    -26.15mA   -15.63mA   -37.84mA
-448mV    -18.28mA   -12.33mA   -27.2mA
312mV     11.8mA     7.606mA    18.2mA
768mV     23.56mA    15.16mA    36.16mA
1.376V    29.47mA    19.17mA    44.23mA
3.124V    32.48mA    22.07mA    47.96mA
3.58V     36.74mA    25.93mA    51.02mA
3.96V     43.15mA    30.92mA    59.98mA
4.34V     52.01mA    37.33mA    73.41mA
5V        73.42mA    51.55mA    108.2mA
[Pullup]
|Voltage   I(typ)   I(min)   I(max)
-2.5V     75.95mA    49.93mA    128.2mA
-2.22V    75.95mA    49.93mA    127.5mA
-2.068V   74.84mA    49.93mA    123mA
-1.916V   71.59mA    49.72mA    116.2mA
-1.384V   54.02mA    39.66mA    85.09mA
-700mV    27.27mA    20.17mA    41.68mA
60mV      -2.071mA   -1.49mA    -3.336mA
440mV     -13.18mA   -9.386mA   -21.47mA
896mV     -22.1mA    -15.49mA   -36.68mA
1.276V    -26.08mA   -17.95mA   -44.18mA
1.656V    -27.53mA   -18.72mA   -47.54mA
5V        -31.92mA   -21.41mA   -56.14mA
[GND_clamp]
|Voltage   I(typ)   I(min)   I(max)
-2.5V     -2.99A     -2.35A     -4.091A
-1.123V   -455.1mA   -463.2mA   -453.7mA
-1.072V   -370.5mA   -399.5mA   -336.3mA
-1.021V   -289.2mA   -337.4mA   -228.6mA
-970mV    -212.6mA   -277.4mA   -140mA
-919mV    -143.6mA   -220.1mA   -87.39mA
-868mV    -87.38mA   -166.5mA   -68.44mA
-817mV    -50.93mA   -117.8mA   -59.12mA
-715mV    -24.98mA   -42.36mA   -39.69mA
-562mV    -7.596mA   -4.111mA   -12.93mA
-358mV    -193.4uA   -101.2uA   -309.3uA
2.5V      13.17nA    0A         -19.29uA
[POWER_clamp]
|Voltage   I(typ)   I(min)   I(max)
-2.5V     42.14mA    30.66mA    68.15mA
-2.294V   38.75mA    27.99mA    63.15mA
-2.039V   34.09mA    24.4mA     56.2mA
-1.529V   23.59mA    16.56mA    40.38mA
-1.223V   16.79mA    11.66mA    29.8mA
-917mV    9.72mA     6.817mA    18.42mA
-815mV    7.285mA    5.246mA    14.27mA
-611mV    2.32mA     2.253mA    4.314mA
-509mV    627.1uA    959.6uA    1.202mA
-458mV    269.3uA    472.4uA    476.3uA
-254mV    28.45uA    20.72uA    43.74uA
2.5V      0A         0A         0A
[Ramp]
| variable   typ   min   max
dV/dt_r   0.771/0.569n   0.553/0.881n   1.066/0.306n
dV/dt_f   0.839/1.000n   0.578/1.585n   1.106/0.553n
R_load = 50.000
[Rising Waveform]
R_fixture= 50.000
V_fixture= 0.0
V_fixture_min= 0.0
V_fixture_max= 0.0
|time   V(typ)   V(min)   V(max)
0s        1.328mV    1.004mV    1.82mV
747ps     1.549mV    1.002mV    18.71mV
1.186ns   -13.88mV   1.254mV    1.444V
1.413ns   98.57mV    -3.594mV   1.666V
1.835ns   772.4mV    -10.08mV   1.753V
2.114ns   1.046V     -746.7uV   1.768V
2.569ns   1.214V     233.5mV    1.776V
3.361ns   1.273V     729.2mV    1.779V
4.419ns   1.284V     893.3mV    1.779V
20ns      1.286V     923.4mV    1.779V
[Rising Waveform]
R_fixture= 50.000
V_fixture= 2.500
V_fixture_min= 2.380
V_fixture_max= 2.630
|time   V(typ)   V(min)   V(max)
0s        1.102V     1.416V     786.3mV
527ps     1.102V     1.416V     800.2mV
683ps     1.102V     1.416V     1.697V
882ps     1.103V     1.416V     2.372V
1.117ns   1.922V     1.416V     2.577V
1.287ns   2.186V     1.416V     2.604V
1.473ns   2.362V     1.456V     2.615V
1.875ns   2.472V     2.175V     2.626V
2.833ns   2.497V     2.361V     2.63V
20ns      2.5V       2.38V      2.63V
[Falling Waveform]
R_fixture= 50.000
V_fixture= 2.500
V_fixture_min= 2.380
V_fixture_max= 2.630
|time   V(typ)   V(min)   V(max)
0s        2.5V       2.38V      2.63V
798ps     2.5V       2.38V      2.62V
1.246ns   2.528V     2.38V      1.63V
1.522ns   2.435V     2.379V     1.171V
1.834ns   2.149V     2.422V     919.1mV
2.288ns   1.673V     2.386V     818.1mV
3.37ns    1.2V       1.992V     788.1mV
4.558ns   1.115V     1.607V     786.3mV
5.634ns   1.104V     1.478V     786.2mV
20ns      1.102V     1.416V     786.1mV
[Falling Waveform]
R_fixture= 50.000
V_fixture= 0.0
V_fixture_min= 0.0
V_fixture_max= 0.0
|time   V(typ)   V(min)   V(max)
0s        1.286V     923.4mV    1.779V
563ps     1.286V     923.3mV    1.767V
698ps     1.286V     923.5mV    997.9mV
922ps     1.288V     923.5mV    319.5mV
1.301ns   392.3mV    923.4mV    26.84mV
1.684ns   84.83mV    903.5mV    7.747mV
1.939ns   28.23mV    384.4mV    4.29mV
2.207ns   12.44mV    158.1mV    2.897mV
3.004ns   2.988mV    18.26mV    1.936mV
20ns      1.328mV    1.004mV    1.82mV
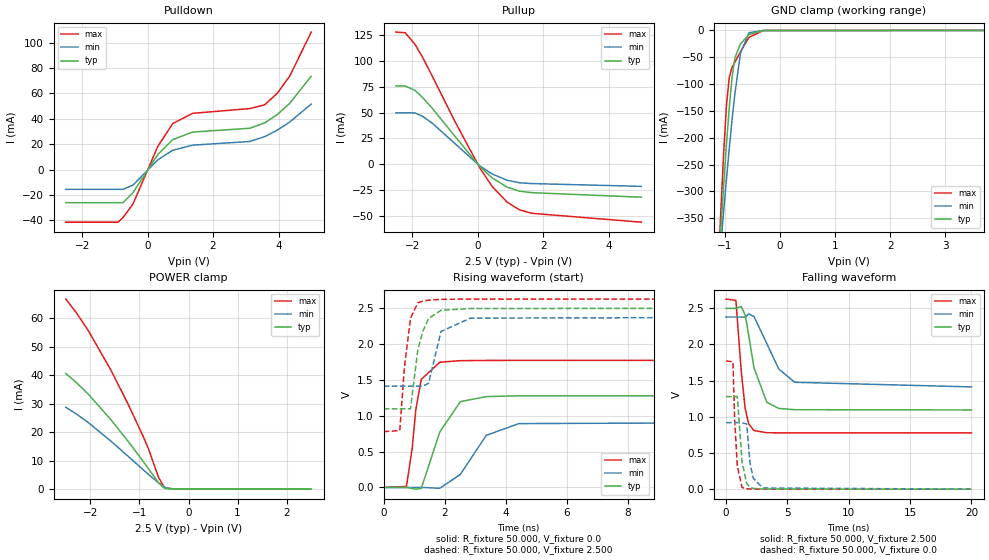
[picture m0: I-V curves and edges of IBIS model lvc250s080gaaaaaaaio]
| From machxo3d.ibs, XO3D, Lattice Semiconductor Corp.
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|   Model lvc250s080gaaaaaaaio
[Model] lvc250s080gaaaaaaaio
Model_type I/O
Polarity   Non-Inverting
Enable   Active-Low
Vinl =  0.700V
Vinh =  1.700V
Vmeas =  1.250V
Cref =  0.0F
Rref =  1.000M
Vref =  0.0V
C_comp   4.200pF   3.800pF   7.500pF
[Temperature Range]   25.000   0.105k   -40.000
[Voltage Range]   2.500V   2.380V   2.630V
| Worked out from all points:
|   slope of the pulldown table from 0 to 0.375 V, typ, clamps not added: 27.2 ohm
|   slope of the pullup table from 0 to 0.375 V, typ, clamps not added: 32.5 ohm
|   GND clamp passes 1 mA (typ) near -0.43 V on its own axis
|   POWER clamp passes 1 mA (typ) near -0.54 V on its own axis
|   rising waveform, R_fixture 50.000, V_fixture 0.0: 20-80 % time 569ps typ, 884ps min, 308ps max; typ from 0 V to 1.28 V
|   rising waveform, R_fixture 50.000, V_fixture 2.500: 20-80 % time 350ps typ, 354ps min, 254ps max; typ from 1.1 V to 2.5 V
|   falling waveform, R_fixture 50.000, V_fixture 2.500: 20-80 % time 1ns typ, 1.59ns min, 548ps max; typ from 2.5 V to 1.09 V
|   falling waveform, R_fixture 50.000, V_fixture 0.0: 20-80 % time 356ps typ, 381ps min, 278ps max; typ from 1.28 V to 0 V
[Pulldown]
|Voltage   I(typ)   I(min)   I(max)
-2.5V     -26.15mA   -15.63mA   -41.49mA
-904mV    -26.15mA   -15.63mA   -41.49mA
-752mV    -26.15mA   -15.63mA   -37.84mA
-448mV    -18.28mA   -12.33mA   -27.2mA
312mV     11.8mA     7.606mA    18.2mA
768mV     23.56mA    15.16mA    36.16mA
1.376V    29.47mA    19.17mA    44.23mA
3.124V    32.48mA    22.07mA    47.96mA
3.58V     36.74mA    25.93mA    51.02mA
3.96V     43.16mA    30.92mA    59.98mA
4.34V     52.02mA    37.33mA    73.41mA
5V        73.43mA    51.54mA    108.2mA
[Pullup]
|Voltage   I(typ)   I(min)   I(max)
-2.5V     75.9mA     49.88mA    128.1mA
-2.22V    75.9mA     49.88mA    127.5mA
-1.916V   71.57mA    49.69mA    116.2mA
-1.688V   64.83mA    46.54mA    103.8mA
-1.384V   54.02mA    39.65mA    85.09mA
-700mV    27.27mA    20.17mA    41.68mA
60mV      -2.071mA   -1.49mA    -3.336mA
440mV     -13.18mA   -9.386mA   -21.47mA
896mV     -22.1mA    -15.49mA   -36.68mA
1.276V    -26.08mA   -17.95mA   -44.18mA
1.656V    -27.53mA   -18.72mA   -47.54mA
5V        -31.92mA   -21.41mA   -56.14mA
[GND_clamp]
|Voltage   I(typ)   I(min)   I(max)
-2.5V     -2.99A     -2.35A     -4.091A
-1.123V   -455.1mA   -463.2mA   -453.7mA
-1.072V   -370.5mA   -399.5mA   -336.3mA
-1.021V   -289.2mA   -337.4mA   -228.6mA
-970mV    -212.6mA   -277.4mA   -140mA
-919mV    -143.6mA   -220.1mA   -87.4mA
-868mV    -87.39mA   -166.5mA   -68.45mA
-817mV    -50.94mA   -117.8mA   -59.13mA
-715mV    -24.99mA   -42.37mA   -39.7mA
-562mV    -7.608mA   -4.125mA   -12.95mA
-307mV    -97.66uA   -51.76uA   -173.8uA
5V        114uA      49.35uA    266.8uA
[POWER_clamp]
|Voltage   I(typ)   I(min)   I(max)
-2.5V     40.55mA    28.7mA     66.64mA
-2.294V   37.53mA    26.47mA    62.05mA
-2.039V   33.25mA    23.31mA    55.5mA
-1.58V    24.33mA    16.84mA    41.69mA
-1.223V   16.6mA     11.41mA    29.54mA
-917mV    9.596mA    6.709mA    18.24mA
-815mV    7.18mA     5.166mA    14.11mA
-611mV    2.243mA    2.205mA    4.167mA
-509mV    558uA      921.7uA    1.059mA
-458mV    208uA      438.7uA    350.8uA
-254mV    2.162uA    3.635uA    1.029uA
2.5V      0A         0A         0A
[Ramp]
| variable   typ   min   max
dV/dt_r   0.768/0.570n   0.552/0.881n   1.063/0.307n
dV/dt_f   0.842/0.993n   0.580/1.592n   1.109/0.549n
R_load = 50.000
[Rising Waveform]
R_fixture= 50.000
V_fixture= 0.0
V_fixture_min= 0.0
V_fixture_max= 0.0
|time   V(typ)   V(min)   V(max)
0s        6.01nV     44.68nV    20.69nV
747ps     230.2uV    -648nV     13.94mV
936ps     -14.97mV   24.06uV    545.7mV
1.052ns   -24.06mV   165.4uV    1.079V
1.232ns   -13.99mV   252.4uV    1.507V
1.84ns    773mV      -11.73mV   1.746V
2.513ns   1.196V     181.8mV    1.768V
3.363ns   1.267V     726.3mV    1.771V
4.424ns   1.278V     889.8mV    1.772V
20ns      1.279V     919.6mV    1.772V
[Rising Waveform]
R_fixture= 50.000
V_fixture= 2.500
V_fixture_min= 2.380
V_fixture_max= 2.630
|time   V(typ)   V(min)   V(max)
0s        1.096V     1.413V     778.2mV
528ps     1.096V     1.413V     793.4mV
682ps     1.096V     1.413V     1.679V
881ps     1.096V     1.413V     2.361V
1.12ns    1.922V     1.413V     2.574V
1.287ns   2.18V      1.413V     2.6V
1.473ns   2.357V     1.453V     2.612V
1.879ns   2.47V      2.175V     2.623V
2.844ns   2.496V     2.361V     2.627V
20ns      2.498V     2.379V     2.627V
[Falling Waveform]
R_fixture= 50.000
V_fixture= 2.500
V_fixture_min= 2.380
V_fixture_max= 2.630
|time   V(typ)   V(min)   V(max)
0s        2.498V     2.379V     2.627V
800ps     2.498V     2.379V     2.61V
1.239ns   2.525V     2.379V     1.631V
1.555ns   2.408V     2.378V     1.117V
1.841ns   2.135V     2.422V     904mV
2.275ns   1.677V     2.386V     809.8mV
3.324ns   1.2V       2.01V      780.2mV
4.304ns   1.116V     1.659V     778.3mV
5.594ns   1.098V     1.477V     778.1mV
20ns      1.095V     1.413V     778.1mV
[Falling Waveform]
R_fixture= 50.000
V_fixture= 0.0
V_fixture_min= 0.0
V_fixture_max= 0.0
|time   V(typ)   V(min)   V(max)
0s        1.279V     919.6mV    1.772V
563ps     1.279V     919.5mV    1.76V
700ps     1.279V     919.7mV    975.9mV
917ps     1.282V     919.7mV    317mV
1.306ns   377.6mV    919.5mV    23.12mV
1.684ns   79.12mV    899.7mV    5.504mV
1.948ns   24.45mV    367.6mV    2.484mV
2.212ns   10.31mV    152.2mV    1.088mV
2.998ns   1.576mV    16.69mV    119.1uV
20ns      14.91nV    100.1nV    33.38nV
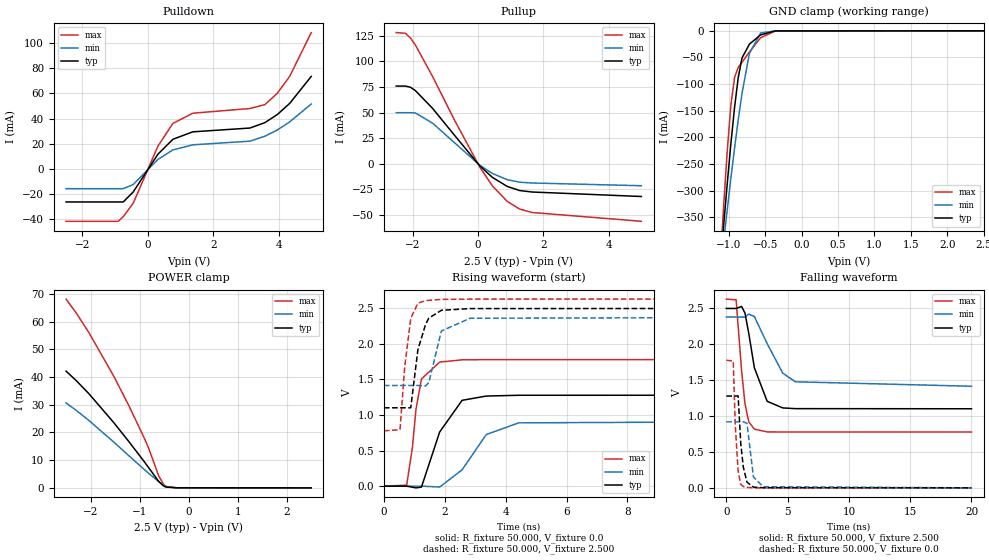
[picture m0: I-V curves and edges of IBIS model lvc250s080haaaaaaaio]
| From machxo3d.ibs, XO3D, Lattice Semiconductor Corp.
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|   Model lvc250s080haaaaaaaio
[Model] lvc250s080haaaaaaaio
Model_type I/O
Polarity   Non-Inverting
Enable   Active-Low
Vinl =  0.700V
Vinh =  1.700V
Vmeas =  1.250V
Cref =  0.0F
Rref =  1.000M
Vref =  0.0V
C_comp   4.200pF   3.800pF   7.500pF
[Temperature Range]   25.000   0.105k   -40.000
[Voltage Range]   2.500V   2.380V   2.630V
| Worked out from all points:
|   slope of the pulldown table from 0 to 0.375 V, typ, clamps not added: 27.2 ohm
|   slope of the pullup table from 0 to 0.375 V, typ, clamps not added: 32.5 ohm
|   GND clamp passes 1 mA (typ) near -0.43 V on its own axis
|   POWER clamp passes 1 mA (typ) near -0.54 V on its own axis
|   rising waveform, R_fixture 50.000, V_fixture 0.0: 20-80 % time 570ps typ, 888ps min, 311ps max; typ from 0 V to 1.28 V
|   rising waveform, R_fixture 50.000, V_fixture 2.500: 20-80 % time 346ps typ, 352ps min, 254ps max; typ from 1.1 V to 2.5 V
|   falling waveform, R_fixture 50.000, V_fixture 2.500: 20-80 % time 1.01ns typ, 1.58ns min, 557ps max; typ from 2.5 V to 1.1 V
|   falling waveform, R_fixture 50.000, V_fixture 0.0: 20-80 % time 357ps typ, 383ps min, 283ps max; typ from 1.28 V to 0 V
[Pulldown]
|Voltage   I(typ)   I(min)   I(max)
-2.5V     -26.15mA   -15.63mA   -41.49mA
-904mV    -26.15mA   -15.63mA   -41.49mA
-752mV    -26.15mA   -15.63mA   -37.84mA
-448mV    -18.28mA   -12.33mA   -27.2mA
312mV     11.8mA     7.606mA    18.2mA
768mV     23.56mA    15.16mA    36.16mA
1.376V    29.47mA    19.17mA    44.23mA
3.124V    32.48mA    22.07mA    47.96mA
3.58V     36.74mA    25.93mA    51.02mA
3.96V     43.15mA    30.92mA    59.98mA
4.34V     52.01mA    37.33mA    73.41mA
5V        73.42mA    51.55mA    108.2mA
[Pullup]
|Voltage   I(typ)   I(min)   I(max)
-2.5V     75.95mA    49.93mA    128.2mA
-2.22V    75.95mA    49.93mA    127.5mA
-2.068V   74.84mA    49.93mA    123mA
-1.916V   71.59mA    49.72mA    116.2mA
-1.384V   54.02mA    39.66mA    85.09mA
-700mV    27.27mA    20.17mA    41.68mA
60mV      -2.071mA   -1.49mA    -3.336mA
440mV     -13.18mA   -9.386mA   -21.47mA
896mV     -22.1mA    -15.49mA   -36.68mA
1.276V    -26.08mA   -17.95mA   -44.18mA
1.656V    -27.53mA   -18.72mA   -47.54mA
5V        -31.92mA   -21.41mA   -56.14mA
[GND_clamp]
|Voltage   I(typ)   I(min)   I(max)
-2.5V     -2.99A     -2.35A     -4.091A
-1.123V   -455.1mA   -463.2mA   -453.7mA
-1.072V   -370.5mA   -399.5mA   -336.3mA
-1.021V   -289.2mA   -337.4mA   -228.6mA
-970mV    -212.6mA   -277.4mA   -140mA
-919mV    -143.6mA   -220.1mA   -87.4mA
-868mV    -87.39mA   -166.5mA   -68.45mA
-817mV    -50.94mA   -117.8mA   -59.13mA
-715mV    -24.99mA   -42.37mA   -39.7mA
-562mV    -7.608mA   -4.125mA   -12.95mA
-358mV    -194.9uA   -98.36uA   -303.6uA
2.5V      13.17nA    0A         -19.29uA
[POWER_clamp]
|Voltage   I(typ)   I(min)   I(max)
-2.5V     42.14mA    30.66mA    68.15mA
-2.294V   38.75mA    27.99mA    63.15mA
-2.039V   34.09mA    24.4mA     56.2mA
-1.529V   23.59mA    16.56mA    40.38mA
-1.223V   16.79mA    11.66mA    29.8mA
-917mV    9.72mA     6.817mA    18.42mA
-815mV    7.285mA    5.246mA    14.27mA
-611mV    2.32mA     2.253mA    4.314mA
-509mV    627.1uA    959.6uA    1.202mA
-458mV    269.3uA    472.4uA    476.3uA
-254mV    28.45uA    20.72uA    43.74uA
2.5V      0A         0A         0A
[Ramp]
| variable   typ   min   max
dV/dt_r   0.768/0.570n   0.552/0.881n   1.068/0.310n
dV/dt_f   0.839/1.000n   0.578/1.585n   1.111/0.558n
R_load = 50.000
[Rising Waveform]
R_fixture= 50.000
V_fixture= 0.0
V_fixture_min= 0.0
V_fixture_max= 0.0
|time   V(typ)   V(min)   V(max)
0s        6.01nV     44.68nV    20.69nV
747ps     230.2uV    -670.3nV   13.94mV
936ps     -14.97mV   24.06uV    545.7mV
1.052ns   -24.06mV   165.4uV    1.079V
1.232ns   -13.99mV   252.4uV    1.507V
1.832ns   762.4mV    -12.21mV   1.745V
2.569ns   1.207V     230.1mV    1.776V
3.363ns   1.267V     726.3mV    1.779V
4.431ns   1.278V     890.2mV    1.779V
20ns      1.279V     919.6mV    1.779V
[Rising Waveform]
R_fixture= 50.000
V_fixture= 2.500
V_fixture_min= 2.380
V_fixture_max= 2.630
|time   V(typ)   V(min)   V(max)
0s        1.102V     1.416V     778.2mV
528ps     1.102V     1.416V     793.4mV
682ps     1.102V     1.416V     1.679V
881ps     1.102V     1.416V     2.361V
1.115ns   1.917V     1.416V     2.573V
1.362ns   2.266V     1.407V     2.608V
1.473ns   2.362V     1.456V     2.614V
1.887ns   2.473V     2.182V     2.626V
2.833ns   2.497V     2.361V     2.63V
20ns      2.5V       2.38V      2.63V
[Falling Waveform]
R_fixture= 50.000
V_fixture= 2.500
V_fixture_min= 2.380
V_fixture_max= 2.630
|time   V(typ)   V(min)   V(max)
0s        2.5V       2.38V      2.63V
798ps     2.5V       2.38V      2.62V
1.246ns   2.528V     2.38V      1.63V
1.522ns   2.435V     2.379V     1.171V
1.834ns   2.149V     2.422V     919.1mV
2.288ns   1.673V     2.387V     818.1mV
3.331ns   1.206V     2.01V      780.2mV
4.603ns   1.114V     1.598V     778.3mV
5.631ns   1.104V     1.478V     778.2mV
20ns      1.102V     1.416V     778.1mV
[Falling Waveform]
R_fixture= 50.000
V_fixture= 0.0
V_fixture_min= 0.0
V_fixture_max= 0.0
|time   V(typ)   V(min)   V(max)
0s        1.279V     919.6mV    1.779V
563ps     1.279V     919.5mV    1.767V
729ps     1.279V     919.7mV    873mV
962ps     1.282V     919.7mV    231.3mV
1.179ns   612.2mV    919.6mV    47.74mV
1.39ns    284.1mV    920.2mV    18.28mV
1.684ns   79.12mV    899.7mV    6.412mV
2.212ns   10.31mV    152.2mV    1.055mV
2.998ns   1.576mV    16.69mV    176.5uV
20ns      14.91nV    100.1nV    30.4nV
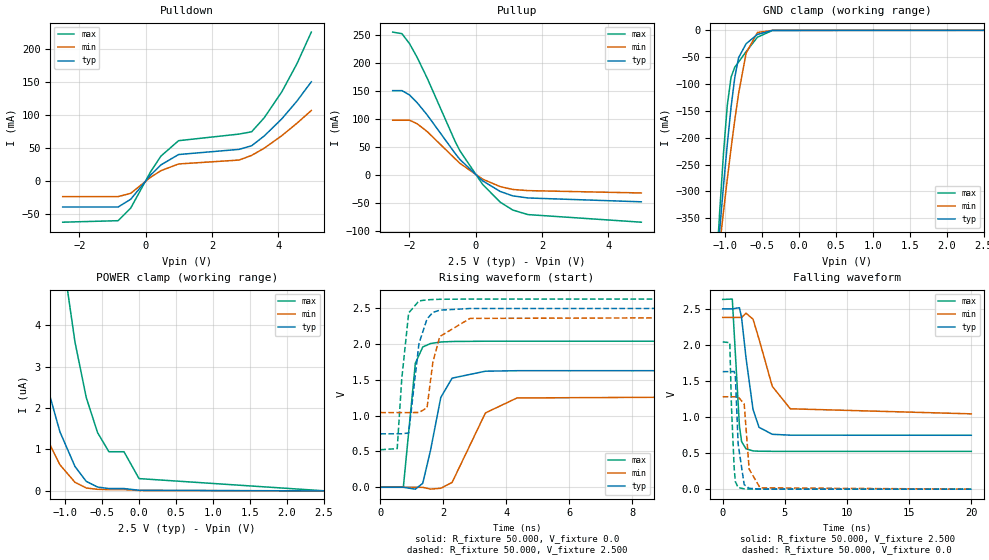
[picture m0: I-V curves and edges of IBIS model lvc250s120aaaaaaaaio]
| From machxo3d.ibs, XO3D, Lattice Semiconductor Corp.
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|   Model lvc250s120aaaaaaaaio
[Model] lvc250s120aaaaaaaaio
Model_type I/O
Polarity   Non-Inverting
Enable   Active-Low
Vinl =  0.700V
Vinh =  1.700V
Vmeas =  1.250V
Cref =  0.0F
Rref =  1.000M
Vref =  0.0V
C_comp   4.200pF   3.800pF   7.500pF
[Temperature Range]   25.000   0.105k   -40.000
[Voltage Range]   2.500V   2.380V   2.630V
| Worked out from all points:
|   slope of the pulldown table from 0 to 0.375 V, typ, clamps not added: 18.1 ohm
|   slope of the pullup table from 0 to 0.375 V, typ, clamps not added: 21.7 ohm
|   GND clamp passes 1 mA (typ) near -0.43 V on its own axis
|   rising waveform, R_fixture 50.000, V_fixture 0.0: 20-80 % time 464ps typ, 826ps min, 232ps max; typ from 0 V to 1.63 V
|   rising waveform, R_fixture 50.000, V_fixture 2.500: 20-80 % time 343ps typ, 347ps min, 237ps max; typ from 0.747 V to 2.5 V
|   falling waveform, R_fixture 50.000, V_fixture 2.500: 20-80 % time 770ps typ, 1.43ns min, 384ps max; typ from 2.5 V to 0.747 V
|   falling waveform, R_fixture 50.000, V_fixture 0.0: 20-80 % time 354ps typ, 377ps min, 258ps max; typ from 1.63 V to 0 V
[Pulldown]
|Voltage   I(typ)   I(min)   I(max)
-2.5V     -39.23mA   -23.44mA   -62.24mA
-828mV    -39.23mA   -23.44mA   -59.96mA
-448mV    -27.42mA   -18.49mA   -40.8mA
160mV     9.666mA    6.229mA    14.91mA
464mV     24.66mA    15.88mA    38.02mA
996mV     40.36mA    26.05mA    61.35mA
2.82V     48.17mA    31.97mA    71.35mA
3.2V      53.66mA    39.06mA    74.88mA
3.58V     68.5mA     49.96mA    96.12mA
4.112V    94.59mA    69.04mA    135.6mA
4.568V    121.5mA    87.88mA    178.2mA
5V        150.6mA    107.1mA    226mA
[Pullup]
|Voltage   I(typ)   I(min)   I(max)
-2.5V     150.4mA    97.59mA    254.8mA
-2.22V    150.4mA    97.59mA    251.9mA
-1.992V   142.6mA    97.59mA    234.1mA
-1.764V   129mA      91.38mA    209.8mA
-1.46V    107.1mA    77.38mA    172.7mA
-624mV    39.01mA    29.3mA     60.73mA
-472mV    27.59mA    20.72mA    43.08mA
212mV     -10.39mA   -7.447mA   -16.81mA
744mV     -29.47mA   -20.78mA   -48.57mA
1.124V    -37.28mA   -25.86mA   -62.59mA
1.58V     -41.03mA   -27.92mA   -70.68mA
5V        -47.88mA   -32.11mA   -84.22mA
[GND_clamp]
|Voltage   I(typ)   I(min)   I(max)
-2.5V     -2.99A     -2.35A     -4.091A
-1.123V   -455.1mA   -463.2mA   -453.6mA
-1.072V   -370.5mA   -399.5mA   -336.3mA
-1.021V   -289.1mA   -337.4mA   -228.5mA
-970mV    -212.6mA   -277.3mA   -139.9mA
-919mV    -143.6mA   -220.1mA   -87.34mA
-868mV    -87.35mA   -166.5mA   -68.39mA
-817mV    -50.9mA    -117.8mA   -59.07mA
-715mV    -24.94mA   -42.34mA   -39.63mA
-562mV    -7.547mA   -4.077mA   -12.85mA
-358mV    -114uA     -53.77uA   -172.8uA
2.5V      0A         0A         0A
[POWER_clamp]
|Voltage   I(typ)   I(min)   I(max)
-2.5V     16.57uA    10.06uA    44.17uA
-2.09V    10.8uA     6.285uA    30.12uA
-1.682V   6.109uA    3.358uA    18.45uA
-1.376V   3.384uA    1.736uA    11.44uA
-1.07V    1.428uA    632.9nA    6.128uA
-866mV    590.6nA    207.8nA    3.594uA
-713mV    230.3nA    70.5nA     2.252uA
-560mV    93.24nA    39.01nA    1.406uA
-407mV    57.67nA    33.39nA    946nA
-203mV    57.67nA    32.38nA    946nA
1mV       16.07nA    10.58nA    297.5nA
2.5V      0A         0A         3.667nA
[Ramp]
| variable   typ   min   max
dV/dt_r   0.978/0.463n   0.769/0.831n   1.225/0.230n
dV/dt_f   1.052/0.772n   0.801/1.429n   1.263/0.384n
R_load = 50.000
[Rising Waveform]
R_fixture= 50.000
V_fixture= 0.0
V_fixture_min= 0.0
V_fixture_max= 0.0
|time   V(typ)   V(min)   V(max)
0s        4.635nV    35nV       15.53nV
734ps     163uV      -3.751uV   6.126mV
1.114ns   -26.45mV   171.9uV    1.734V
1.349ns   55.5mV     -1.083mV   1.96V
1.595ns   514.4mV    -25.57mV   2.009V
1.922ns   1.255V     -13.93mV   2.03V
2.281ns   1.525V     67.4mV     2.037V
3.34ns    1.622V     1.039V     2.041V
4.343ns   1.629V     1.248V     2.041V
20ns      1.629V     1.281V     2.041V
[Rising Waveform]
R_fixture= 50.000
V_fixture= 2.500
V_fixture_min= 2.380
V_fixture_max= 2.630
|time   V(typ)   V(min)   V(max)
0s        747.2mV    1.044V     524.3mV
538ps     747.2mV    1.044V     540.2mV
682ps     747.3mV    1.044V     1.513V
902ps     759mV      1.044V     2.436V
1.228ns   2.007V     1.045V     2.604V
1.485ns   2.353V     1.11V      2.619V
1.671ns   2.444V     1.75V      2.624V
1.891ns   2.475V     2.107V     2.627V
2.851ns   2.498V     2.36V      2.63V
20ns      2.5V       2.38V      2.63V
[Falling Waveform]
R_fixture= 50.000
V_fixture= 2.500
V_fixture_min= 2.380
V_fixture_max= 2.630
|time   V(typ)   V(min)   V(max)
0s        2.5V       2.38V      2.63V
772ps     2.5V       2.38V      2.635V
1.345ns   2.515V     2.38V      877mV
1.519ns   2.377V     2.38V      659.4mV
1.875ns   1.82V      2.439V     559.3mV
2.44ns    1.104V     2.356V     530.3mV
2.92ns    857.7mV    2.081V     526mV
3.989ns   760.6mV    1.425V     524.4mV
5.437ns   748.4mV    1.114V     524.4mV
20ns      747.1mV    1.044V     524.3mV
[Falling Waveform]
R_fixture= 50.000
V_fixture= 0.0
V_fixture_min= 0.0
V_fixture_max= 0.0
|time   V(typ)   V(min)   V(max)
0s        1.629V     1.281V     2.041V
571ps     1.629V     1.281V     2.031V
701ps     1.629V     1.281V     1.159V
923ps     1.632V     1.281V     291.9mV
1.019ns   1.555V     1.281V     103.2mV
1.241ns   625.6mV    1.281V     23.89mV
1.729ns   62.71mV    1.18V      3.668mV
2.127ns   11.96mV    277.5mV    1.1mV
3.003ns   1.47mV     18.75mV    118.1uV
20ns      54.38nV    182.8nV    32.93nV
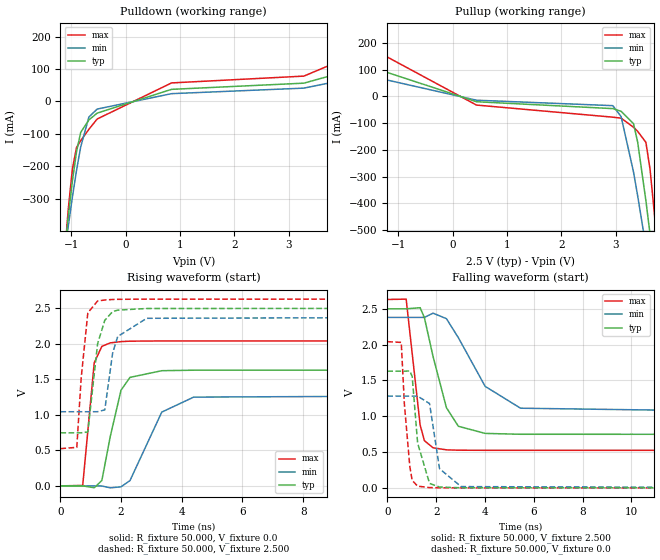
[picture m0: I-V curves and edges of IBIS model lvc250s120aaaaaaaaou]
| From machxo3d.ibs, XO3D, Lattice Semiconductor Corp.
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|   Model lvc250s120aaaaaaaaou
[Model] lvc250s120aaaaaaaaou
Model_type Output
Polarity   Non-Inverting
Enable   Active-High
Vmeas =  1.250V
Cref =  0.0F
Rref =  1.000M
Vref =  0.0V
C_comp   4.200pF   3.800pF   7.500pF
[Temperature Range]   25.000   0.105k   -40.000
[Voltage Range]   2.500V   2.380V   2.630V
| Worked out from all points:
|   slope of the pulldown table from 0 to 0.375 V, typ, clamps not added: 18.1 ohm
|   slope of the pullup table from 0 to 0.375 V, typ, clamps not added: 21.7 ohm
|   rising waveform, R_fixture 50.000, V_fixture 0.0: 20-80 % time 466ps typ, 826ps min, 232ps max; typ from 0 V to 1.63 V
|   rising waveform, R_fixture 50.000, V_fixture 2.500: 20-80 % time 344ps typ, 349ps min, 237ps max; typ from 0.747 V to 2.5 V
|   falling waveform, R_fixture 50.000, V_fixture 2.500: 20-80 % time 769ps typ, 1.45ns min, 385ps max; typ from 2.5 V to 0.747 V
|   falling waveform, R_fixture 50.000, V_fixture 0.0: 20-80 % time 354ps typ, 375ps min, 258ps max; typ from 1.63 V to 0 V
[Pulldown]
|Voltage   I(typ)   I(min)   I(max)
-2.5V     -2.991A    -2.351A    -4.092A
-1.132V   -477.3mA   -478.1mA   -490.1mA
-1.056V   -355mA     -384.2mA   -331.8mA
-980mV    -244.9mA   -294.8mA   -207.7mA
-904mV    -155.3mA   -212.2mA   -141.7mA
-828mV    -95.41mA   -140.5mA   -120.9mA
-676mV    -56.77mA   -47.71mA   -85.72mA
-524mV    -35.9mA    -23.48mA   -54.06mA
844mV     37.3mA     24.02mA    57.11mA
3.276V    56.34mA    41.03mA    78.1mA
4.188V    98.8mA     72.04mA    142.2mA
5V        150.6mA    107.1mA    226.1mA
[Pullup]
|Voltage   I(typ)   I(min)   I(max)
-2.5V     150.4mA    97.6mA     254.9mA
-1.992V   142.6mA    97.6mA     234.1mA
440mV     -19.77mA   -14.08mA   -32.21mA
2.948V    -45.51mA   -34.45mA   -77.55mA
3.1V      -55.71mA   -75.32mA   -81.24mA
3.328V    -102mA     -282.7mA   -115.2mA
3.404V    -170.7mA   -371.5mA   -130.5mA
3.556V    -390.2mA   -561.5mA   -171.8mA
3.632V    -516.1mA   -660.2mA   -272.5mA
3.708V    -646.7mA   -760.5mA   -430mA
3.784V    -780.5mA   -862mA     -608.4mA
5V        -3.038A    -2.551A    -3.824A
[Ramp]
| variable   typ   min   max
dV/dt_r   0.978/0.463n   0.769/0.831n   1.225/0.230n
dV/dt_f   1.052/0.772n   0.801/1.429n   1.263/0.384n
R_load = 50.000
[Rising Waveform]
R_fixture= 50.000
V_fixture= 0.0
V_fixture_min= 0.0
V_fixture_max= 0.0
|time   V(typ)   V(min)   V(max)
0s        4.635nV    35nV       15.53nV
734ps     157.2uV    -6.265uV   6.126mV
1.114ns   -26.45mV   156.5uV    1.734V
1.365ns   75.54mV    -1.816mV   1.965V
1.644ns   699.1mV    -28.07mV   2.014V
1.997ns   1.348V     -13.39mV   2.032V
2.293ns   1.528V     75.44mV    2.038V
3.34ns    1.622V     1.039V     2.041V
4.391ns   1.629V     1.25V      2.041V
20ns      1.629V     1.281V     2.041V
[Rising Waveform]
R_fixture= 50.000
V_fixture= 2.500
V_fixture_min= 2.380
V_fixture_max= 2.630
|time   V(typ)   V(min)   V(max)
0s        747.2mV    1.044V     524.3mV
539ps     747.2mV    1.044V     542.3mV
682ps     747.2mV    1.044V     1.513V
902ps     759mV      1.044V     2.436V
1.224ns   2V         1.045V     2.604V
1.461ns   2.331V     1.07V      2.618V
1.721ns   2.455V     1.872V     2.625V
1.888ns   2.475V     2.104V     2.627V
2.845ns   2.498V     2.36V      2.63V
20ns      2.5V       2.38V      2.63V
[Falling Waveform]
R_fixture= 50.000
V_fixture= 2.500
V_fixture_min= 2.380
V_fixture_max= 2.630
|time   V(typ)   V(min)   V(max)
0s        2.5V       2.38V      2.63V
772ps     2.5V       2.38V      2.635V
1.345ns   2.515V     2.38V      877mV
1.519ns   2.377V     2.38V      659.4mV
1.874ns   1.833V     2.439V     559.4mV
2.422ns   1.119V     2.362V     530.6mV
2.91ns    860.1mV    2.097V     525.8mV
4.009ns   760.2mV    1.417V     524.4mV
5.458ns   748.3mV    1.112V     524.3mV
20ns      747.1mV    1.044V     524.3mV
[Falling Waveform]
R_fixture= 50.000
V_fixture= 0.0
V_fixture_min= 0.0
V_fixture_max= 0.0
|time   V(typ)   V(min)   V(max)
0s        1.629V     1.281V     2.041V
571ps     1.629V     1.281V     2.031V
700ps     1.629V     1.281V     1.164V
923ps     1.632V     1.281V     291.9mV
1.019ns   1.555V     1.281V     103.1mV
1.241ns   625.6mV    1.281V     23.79mV
1.73ns    61.95mV    1.177V     3.864mV
2.139ns   11.69mV    267.2mV    993.8uV
3.023ns   1.354mV    17.63mV    85.25uV
20ns      54.16nV    183.7nV    32.9nV
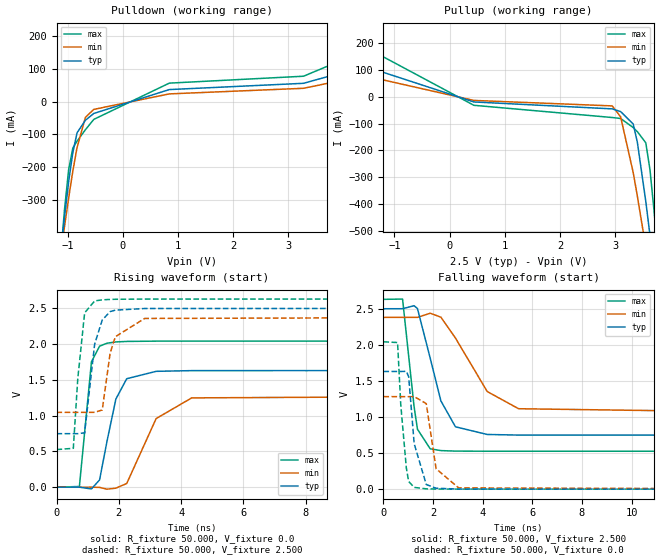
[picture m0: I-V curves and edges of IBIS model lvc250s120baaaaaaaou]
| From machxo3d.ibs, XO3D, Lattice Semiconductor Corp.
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|   Model lvc250s120baaaaaaaou
[Model] lvc250s120baaaaaaaou
Model_type Output
Polarity   Non-Inverting
Enable   Active-High
Vmeas =  1.250V
Cref =  0.0F
Rref =  1.000M
Vref =  0.0V
C_comp   4.200pF   3.800pF   7.500pF
[Temperature Range]   25.000   0.105k   -40.000
[Voltage Range]   2.500V   2.380V   2.630V
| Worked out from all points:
|   slope of the pulldown table from 0 to 0.375 V, typ, clamps not added: 18.1 ohm
|   slope of the pullup table from 0 to 0.375 V, typ, clamps not added: 21.7 ohm
|   rising waveform, R_fixture 50.000, V_fixture 0.0: 20-80 % time 465ps typ, 826ps min, 230ps max; typ from 0.001 V to 1.63 V
|   rising waveform, R_fixture 50.000, V_fixture 2.500: 20-80 % time 343ps typ, 348ps min, 237ps max; typ from 0.749 V to 2.5 V
|   falling waveform, R_fixture 50.000, V_fixture 2.500: 20-80 % time 768ps typ, 1.44ns min, 386ps max; typ from 2.5 V to 0.749 V
|   falling waveform, R_fixture 50.000, V_fixture 0.0: 20-80 % time 357ps typ, 380ps min, 259ps max; typ from 1.63 V to 0.001 V
[Pulldown]
|Voltage   I(typ)   I(min)   I(max)
-2.5V     -2.991A    -2.351A    -4.092A
-1.132V   -477.3mA   -478.1mA   -490.2mA
-1.056V   -355.1mA   -384.2mA   -331.9mA
-980mV    -245mA     -294.8mA   -207.8mA
-904mV    -155.3mA   -212.2mA   -141.8mA
-828mV    -95.44mA   -140.5mA   -121mA
-676mV    -56.81mA   -47.74mA   -85.78mA
-524mV    -35.96mA   -23.52mA   -54.15mA
844mV     37.22mA    23.97mA    56.96mA
3.276V    56.41mA    41.13mA    78.15mA
4.188V    99.26mA    72.84mA    142.5mA
5V        152.3mA    109.4mA    227.3mA
[Pullup]
|Voltage   I(typ)   I(min)   I(max)
-2.5V     151.7mA    98.76mA    256.1mA
-1.992V   143.4mA    98.71mA    234.8mA
440mV     -19.8mA    -14.1mA    -32.27mA
2.948V    -45.58mA   -34.48mA   -77.69mA
3.1V      -55.74mA   -75.33mA   -81.34mA
3.328V    -102mA     -282.8mA   -115.2mA
3.404V    -170.8mA   -371.6mA   -130.5mA
3.556V    -390.2mA   -561.5mA   -171.8mA
3.632V    -516.1mA   -660.2mA   -272.6mA
3.708V    -646.8mA   -760.5mA   -430.1mA
3.784V    -780.5mA   -862mA     -608.4mA
5V        -3.038A    -2.551A    -3.824A
[Ramp]
| variable   typ   min   max
dV/dt_r   0.978/0.463n   0.769/0.826n   1.224/0.230n
dV/dt_f   1.051/0.774n   0.800/1.426n   1.262/0.386n
R_load = 50.000
[Rising Waveform]
R_fixture= 50.000
V_fixture= 0.0
V_fixture_min= 0.0
V_fixture_max= 0.0
|time   V(typ)   V(min)   V(max)
0s        990.6uV    778.5uV    1.315mV
734ps     1.141mV    771.1uV    10.75mV
1.121ns   -23.34mV   1.061mV    1.753V
1.382ns   103mV      -1.816mV   1.972V
1.619ns   640.1mV    -26.63mV   2.013V
1.905ns   1.233V     -12.38mV   2.031V
2.254ns   1.517V     52.98mV    2.038V
3.197ns   1.62V      959.7mV    2.042V
4.339ns   1.63V      1.249V     2.042V
20ns      1.631V     1.283V     2.042V
[Rising Waveform]
R_fixture= 50.000
V_fixture= 2.500
V_fixture_min= 2.380
V_fixture_max= 2.630
|time   V(typ)   V(min)   V(max)
0s        748.9mV    1.046V     526.3mV
539ps     748.9mV    1.046V     544.5mV
682ps     748.9mV    1.046V     1.518V
902ps     760.8mV    1.046V     2.437V
1.224ns   2.001V     1.047V     2.604V
1.467ns   2.337V     1.08V      2.619V
1.721ns   2.455V     1.874V     2.625V
1.888ns   2.475V     2.104V     2.627V
2.83ns    2.498V     2.359V     2.63V
20ns      2.5V       2.38V      2.63V
[Falling Waveform]
R_fixture= 50.000
V_fixture= 2.500
V_fixture_min= 2.380
V_fixture_max= 2.630
|time   V(typ)   V(min)   V(max)
0s        2.5V       2.38V      2.63V
772ps     2.5V       2.38V      2.634V
1.235ns   2.542V     2.38V      1.149V
1.372ns   2.503V     2.38V      831.4mV
1.886ns   1.815V     2.438V     560.2mV
2.317ns   1.223V     2.383V     535mV
2.903ns   864.7mV    2.094V     527.9mV
4.184ns   758.5mV    1.353V     526.3mV
5.447ns   749.9mV    1.115V     526.2mV
20ns      748.8mV    1.046V     526.2mV
[Falling Waveform]
R_fixture= 50.000
V_fixture= 0.0
V_fixture_min= 0.0
V_fixture_max= 0.0
|time   V(typ)   V(min)   V(max)
0s        1.631V     1.283V     2.042V
571ps     1.631V     1.283V     2.032V
700ps     1.631V     1.283V     1.168V
923ps     1.633V     1.283V     297.4mV
1.018ns   1.56V      1.283V     107.2mV
1.241ns   629.4mV    1.283V     25.41mV
1.727ns   65.2mV     1.186V     5.358mV
2.123ns   13.53mV    283.6mV    2.402mV
3.032ns   2.357mV    18.5mV     1.429mV
20ns      990.6uV    778.6uV    1.315mV
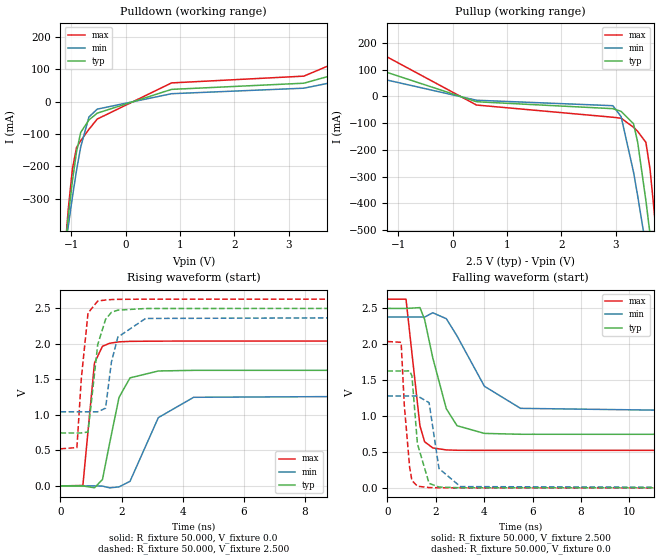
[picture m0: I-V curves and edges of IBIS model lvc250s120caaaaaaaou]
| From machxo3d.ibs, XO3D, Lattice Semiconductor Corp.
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|   Model lvc250s120caaaaaaaou
[Model] lvc250s120caaaaaaaou
Model_type Output
Polarity   Non-Inverting
Enable   Active-High
Vmeas =  1.250V
Cref =  0.0F
Rref =  1.000M
Vref =  0.0V
C_comp   4.200pF   3.800pF   7.500pF
[Temperature Range]   25.000   0.105k   -40.000
[Voltage Range]   2.500V   2.380V   2.630V
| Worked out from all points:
|   slope of the pulldown table from 0 to 0.375 V, typ, clamps not added: 18.1 ohm
|   slope of the pullup table from 0 to 0.375 V, typ, clamps not added: 21.7 ohm
|   rising waveform, R_fixture 50.000, V_fixture 0.0: 20-80 % time 466ps typ, 826ps min, 232ps max; typ from 0 V to 1.63 V
|   rising waveform, R_fixture 50.000, V_fixture 2.500: 20-80 % time 345ps typ, 351ps min, 238ps max; typ from 0.745 V to 2.5 V
|   falling waveform, R_fixture 50.000, V_fixture 2.500: 20-80 % time 767ps typ, 1.42ns min, 383ps max; typ from 2.5 V to 0.745 V
|   falling waveform, R_fixture 50.000, V_fixture 0.0: 20-80 % time 351ps typ, 374ps min, 256ps max; typ from 1.63 V to 0 V
[Pulldown]
|Voltage   I(typ)   I(min)   I(max)
-2.5V     -2.991A    -2.351A    -4.092A
-1.132V   -477.3mA   -478.1mA   -490.2mA
-1.056V   -355.1mA   -384.2mA   -331.9mA
-980mV    -245mA     -294.8mA   -207.8mA
-904mV    -155.4mA   -212.2mA   -141.8mA
-828mV    -95.45mA   -140.5mA   -121mA
-676mV    -56.82mA   -47.75mA   -85.79mA
-524mV    -35.97mA   -23.54mA   -54.16mA
844mV     37.4mA     24.05mA    57.34mA
3.276V    56.42mA    41.07mA    78.25mA
4.188V    98.93mA    72.11mA    142.4mA
5V        150.8mA    107.2mA    226.4mA
[Pullup]
|Voltage   I(typ)   I(min)   I(max)
-2.5V     150.6mA    97.67mA    255.2mA
-1.992V   142.7mA    97.67mA    234.4mA
440mV     -19.66mA   -14.04mA   -31.96mA
2.948V    -45.59mA   -34.49mA   -77.68mA
3.1V      -55.75mA   -75.34mA   -81.35mA
3.328V    -102mA     -282.8mA   -115.2mA
3.404V    -170.8mA   -371.6mA   -130.5mA
3.556V    -390.2mA   -561.5mA   -171.8mA
3.632V    -516.1mA   -660.2mA   -272.6mA
3.708V    -646.8mA   -760.5mA   -430.1mA
3.784V    -780.5mA   -862mA     -608.4mA
5V        -3.038A    -2.551A    -3.824A
[Ramp]
| variable   typ   min   max
dV/dt_r   0.976/0.464n   0.768/0.831n   1.223/0.231n
dV/dt_f   1.052/0.771n   0.802/1.426n   1.263/0.383n
R_load = 50.000
[Rising Waveform]
R_fixture= 50.000
V_fixture= 0.0
V_fixture_min= 0.0
V_fixture_max= 0.0
|time   V(typ)   V(min)   V(max)
0s        4.486nV    34.65nV    14.98nV
734ps     161.5uV    -6.206uV   6.454mV
1.114ns   -26.25mV   156.1uV    1.73V
1.376ns   90.91mV    -2.52mV    1.965V
1.611ns   602.6mV    -27.28mV   2.007V
1.917ns   1.245V     -13.85mV   2.027V
2.277ns   1.52V      64.83mV    2.034V
3.204ns   1.617V     960.8mV    2.037V
4.361ns   1.626V     1.247V     2.038V
20ns      1.627V     1.28V      2.038V
[Rising Waveform]
R_fixture= 50.000
V_fixture= 2.500
V_fixture_min= 2.380
V_fixture_max= 2.630
|time   V(typ)   V(min)   V(max)
0s        745.3mV    1.043V     522.1mV
539ps     745.3mV    1.043V     539.8mV
682ps     745.4mV    1.043V     1.506V
903ps     758.3mV    1.043V     2.433V
1.22ns    1.988V     1.043V     2.601V
1.477ns   2.343V     1.094V     2.616V
1.669ns   2.442V     1.743V     2.622V
1.879ns   2.473V     2.094V     2.625V
2.788ns   2.496V     2.356V     2.627V
20ns      2.499V     2.379V     2.628V
[Falling Waveform]
R_fixture= 50.000
V_fixture= 2.500
V_fixture_min= 2.380
V_fixture_max= 2.630
|time   V(typ)   V(min)   V(max)
0s        2.499V     2.379V     2.628V
772ps     2.498V     2.379V     2.627V
1.347ns   2.51V      2.379V     864.9mV
1.54ns    2.347V     2.378V     642.6mV
1.877ns   1.812V     2.438V     556.3mV
2.437ns   1.102V     2.356V     528mV
2.881ns   865.2mV    2.115V     523.7mV
4.011ns   758.3mV    1.415V     522.2mV
5.505ns   746.2mV    1.107V     522.1mV
20ns      745.3mV    1.043V     522.1mV
[Falling Waveform]
R_fixture= 50.000
V_fixture= 0.0
V_fixture_min= 0.0
V_fixture_max= 0.0
|time   V(typ)   V(min)   V(max)
0s        1.627V     1.28V      2.038V
571ps     1.627V     1.28V      2.027V
701ps     1.627V     1.28V      1.152V
922ps     1.629V     1.28V      287.6mV
1.017ns   1.559V     1.28V      101.7mV
1.244ns   614.5mV    1.28V      22.86mV
1.726ns   62.04mV    1.186V     3.857mV
2.135ns   11.71mV    269.1mV    986.1uV
3.02ns    1.36mV     17.58mV    83.23uV
20ns      49nV       178nV      28.93nV
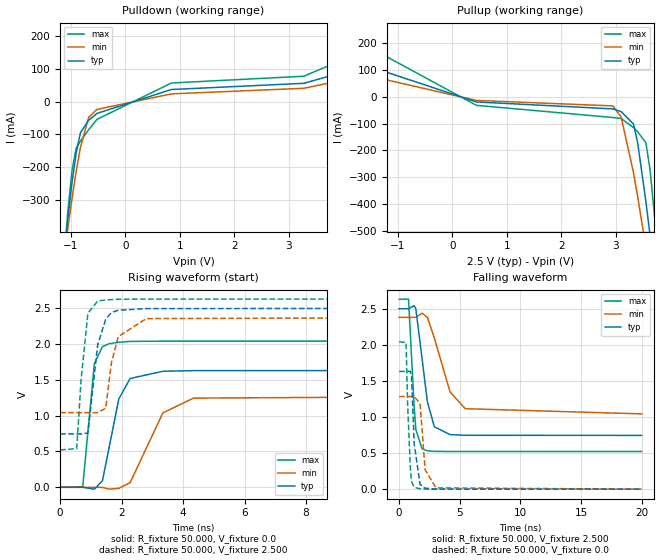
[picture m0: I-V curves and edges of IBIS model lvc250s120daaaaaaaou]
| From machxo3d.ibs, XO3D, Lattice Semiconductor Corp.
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|   Model lvc250s120daaaaaaaou
[Model] lvc250s120daaaaaaaou
Model_type Output
Polarity   Non-Inverting
Enable   Active-High
Vmeas =  1.250V
Cref =  0.0F
Rref =  1.000M
Vref =  0.0V
C_comp   4.200pF   3.800pF   7.500pF
[Temperature Range]   25.000   0.105k   -40.000
[Voltage Range]   2.500V   2.380V   2.630V
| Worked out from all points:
|   slope of the pulldown table from 0 to 0.375 V, typ, clamps not added: 18.1 ohm
|   slope of the pullup table from 0 to 0.375 V, typ, clamps not added: 21.7 ohm
|   rising waveform, R_fixture 50.000, V_fixture 0.0: 20-80 % time 468ps typ, 831ps min, 233ps max; typ from 0 V to 1.63 V
|   rising waveform, R_fixture 50.000, V_fixture 2.500: 20-80 % time 346ps typ, 348ps min, 239ps max; typ from 0.745 V to 2.5 V
|   falling waveform, R_fixture 50.000, V_fixture 2.500: 20-80 % time 771ps typ, 1.44ns min, 387ps max; typ from 2.5 V to 0.745 V
|   falling waveform, R_fixture 50.000, V_fixture 0.0: 20-80 % time 358ps typ, 378ps min, 259ps max; typ from 1.63 V to 0 V
[Pulldown]
|Voltage   I(typ)   I(min)   I(max)
-2.5V     -2.991A    -2.351A    -4.092A
-1.132V   -477.3mA   -478.1mA   -490.2mA
-1.056V   -355.1mA   -384.2mA   -331.9mA
-980mV    -245mA     -294.8mA   -207.8mA
-904mV    -155.4mA   -212.2mA   -141.8mA
-828mV    -95.45mA   -140.5mA   -121mA
-676mV    -56.82mA   -47.75mA   -85.79mA
-524mV    -35.97mA   -23.54mA   -54.16mA
844mV     37.4mA     24.05mA    57.34mA
3.276V    56.41mA    41.13mA    78.15mA
4.188V    99.26mA    72.84mA    142.5mA
5V        152.3mA    109.4mA    227.3mA
[Pullup]
|Voltage   I(typ)   I(min)   I(max)
-2.5V     151.7mA    98.76mA    256.1mA
-1.992V   143.4mA    98.71mA    234.8mA
440mV     -19.8mA    -14.1mA    -32.27mA
2.948V    -45.59mA   -34.49mA   -77.68mA
3.1V      -55.75mA   -75.34mA   -81.35mA
3.328V    -102mA     -282.8mA   -115.2mA
3.404V    -170.8mA   -371.6mA   -130.5mA
3.556V    -390.2mA   -561.5mA   -171.8mA
3.632V    -516.1mA   -660.2mA   -272.6mA
3.708V    -646.8mA   -760.5mA   -430.1mA
3.784V    -780.5mA   -862mA     -608.4mA
5V        -3.038A    -2.551A    -3.824A
[Ramp]
| variable   typ   min   max
dV/dt_r   0.979/0.467n   0.770/0.833n   1.225/0.232n
dV/dt_f   1.053/0.777n   0.802/1.439n   1.265/0.387n
R_load = 50.000
[Rising Waveform]
R_fixture= 50.000
V_fixture= 0.0
V_fixture_min= 0.0
V_fixture_max= 0.0
|time   V(typ)   V(min)   V(max)
0s        4.486nV    34.65nV    14.98nV
734ps     161.5uV    -6.223uV   6.455mV
1.114ns   -26.25mV   156.3uV    1.73V
1.376ns   90.91mV    -2.52mV    1.965V
1.598ns   564.5mV    -26.34mV   2.006V
1.911ns   1.236V     -14.18mV   2.027V
2.277ns   1.52V      64.83mV    2.038V
3.344ns   1.621V     1.04V      2.042V
4.34ns    1.63V      1.246V     2.042V
20ns      1.631V     1.283V     2.042V
[Rising Waveform]
R_fixture= 50.000
V_fixture= 2.500
V_fixture_min= 2.380
V_fixture_max= 2.630
|time   V(typ)   V(min)   V(max)
0s        745.3mV    1.043V     522.1mV
539ps     745.3mV    1.043V     539.8mV
682ps     745.4mV    1.043V     1.506V
903ps     758.3mV    1.043V     2.433V
1.22ns    1.988V     1.043V     2.601V
1.483ns   2.349V     1.105V     2.618V
1.669ns   2.442V     1.743V     2.623V
1.891ns   2.474V     2.105V     2.627V
2.805ns   2.497V     2.357V     2.63V
20ns      2.5V       2.38V      2.63V
[Falling Waveform]
R_fixture= 50.000
V_fixture= 2.500
V_fixture_min= 2.380
V_fixture_max= 2.630
|time   V(typ)   V(min)   V(max)
0s        2.5V       2.38V      2.63V
772ps     2.5V       2.38V      2.634V
1.235ns   2.542V     2.38V      1.149V
1.372ns   2.503V     2.381V     831.4mV
1.886ns   1.815V     2.438V     560.2mV
2.329ns   1.21V      2.381V     531.3mV
2.903ns   864.7mV    2.094V     523.8mV
4.196ns   756.1mV    1.348V     522.1mV
5.447ns   746.4mV    1.115V     522.1mV
20ns      745.3mV    1.043V     522.1mV
[Falling Waveform]
R_fixture= 50.000
V_fixture= 0.0
V_fixture_min= 0.0
V_fixture_max= 0.0
|time   V(typ)   V(min)   V(max)
0s        1.631V     1.283V     2.042V
571ps     1.631V     1.283V     2.032V
700ps     1.631V     1.283V     1.168V
923ps     1.633V     1.283V     297.4mV
1.018ns   1.56V      1.283V     107.2mV
1.241ns   629.4mV    1.283V     25.41mV
1.727ns   65.2mV     1.186V     4.448mV
2.139ns   12.98mV    269.7mV    1.073mV
3.032ns   1.65mV     18.5mV     109.2uV
20ns      45.96nV    178.2nV    23.83nV
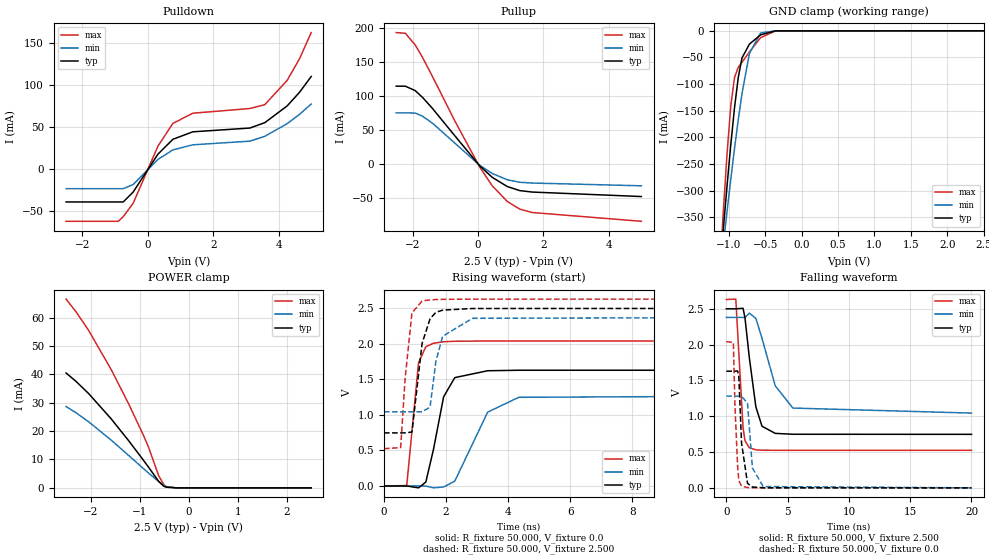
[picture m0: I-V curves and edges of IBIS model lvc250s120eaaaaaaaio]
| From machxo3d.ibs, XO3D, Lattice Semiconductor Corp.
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|   Model lvc250s120eaaaaaaaio
[Model] lvc250s120eaaaaaaaio
Model_type I/O
Polarity   Non-Inverting
Enable   Active-Low
Vinl =  0.700V
Vinh =  1.700V
Vmeas =  1.250V
Cref =  0.0F
Rref =  1.000M
Vref =  0.0V
C_comp   4.200pF   3.800pF   7.500pF
[Temperature Range]   25.000   0.105k   -40.000
[Voltage Range]   2.500V   2.380V   2.630V
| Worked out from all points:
|   slope of the pulldown table from 0 to 0.375 V, typ, clamps not added: 18.1 ohm
|   slope of the pullup table from 0 to 0.375 V, typ, clamps not added: 21.7 ohm
|   GND clamp passes 1 mA (typ) near -0.43 V on its own axis
|   POWER clamp passes 1 mA (typ) near -0.54 V on its own axis
|   rising waveform, R_fixture 50.000, V_fixture 0.0: 20-80 % time 464ps typ, 826ps min, 232ps max; typ from 0 V to 1.63 V
|   rising waveform, R_fixture 50.000, V_fixture 2.500: 20-80 % time 344ps typ, 347ps min, 237ps max; typ from 0.747 V to 2.5 V
|   falling waveform, R_fixture 50.000, V_fixture 2.500: 20-80 % time 771ps typ, 1.44ns min, 385ps max; typ from 2.5 V to 0.747 V
|   falling waveform, R_fixture 50.000, V_fixture 0.0: 20-80 % time 354ps typ, 377ps min, 258ps max; typ from 1.63 V to 0 V
[Pulldown]
|Voltage   I(typ)   I(min)   I(max)
-2.5V     -39.23mA   -23.44mA   -62.24mA
-904mV    -39.23mA   -23.44mA   -62.24mA
-752mV    -39.23mA   -23.44mA   -56.76mA
-448mV    -27.42mA   -18.49mA   -40.8mA
312mV     17.71mA    11.41mA    27.31mA
768mV     35.33mA    22.74mA    54.24mA
1.376V    44.21mA    28.76mA    66.35mA
3.124V    48.72mA    33.11mA    71.94mA
3.58V     55.12mA    38.9mA     76.54mA
4.264V    75.07mA    53.91mA    105.5mA
4.644V    91.33mA    65.11mA    131.3mA
5V        110.1mA    77.29mA    162.3mA
[Pullup]
|Voltage   I(typ)   I(min)   I(max)
-2.5V     114.1mA    74.93mA    192.8mA
-2.22V    114.1mA    74.93mA    191.7mA
-1.916V   107.5mA    74.62mA    174.5mA
-1.688V   97.32mA    69.86mA    155.8mA
-1.384V   81.06mA    59.5mA     127.7mA
-700mV    40.91mA    30.25mA    62.53mA
60mV      -3.106mA   -2.235mA   -5.004mA
440mV     -19.77mA   -14.08mA   -32.21mA
896mV     -33.15mA   -23.24mA   -55.01mA
1.276V    -39.13mA   -26.93mA   -66.27mA
1.656V    -41.29mA   -28.07mA   -71.31mA
5V        -47.88mA   -32.11mA   -84.22mA
[GND_clamp]
|Voltage   I(typ)   I(min)   I(max)
-2.5V     -2.99A     -2.35A     -4.091A
-1.123V   -455.1mA   -463.2mA   -453.6mA
-1.072V   -370.5mA   -399.5mA   -336.3mA
-1.021V   -289.1mA   -337.4mA   -228.5mA
-970mV    -212.6mA   -277.3mA   -139.9mA
-919mV    -143.6mA   -220.1mA   -87.34mA
-868mV    -87.35mA   -166.5mA   -68.39mA
-817mV    -50.9mA    -117.8mA   -59.07mA
-715mV    -24.94mA   -42.34mA   -39.63mA
-562mV    -7.547mA   -4.077mA   -12.85mA
-358mV    -114uA     -53.77uA   -172.8uA
2.5V      0A         0A         0A
[POWER_clamp]
|Voltage   I(typ)   I(min)   I(max)
-2.5V     40.49mA    28.66mA    66.53mA
-2.294V   37.48mA    26.44mA    61.99mA
-2.039V   33.22mA    23.28mA    55.47mA
-1.58V    24.32mA    16.83mA    41.7mA
-1.223V   16.6mA     11.41mA    29.58mA
-917mV    9.616mA    6.712mA    18.32mA
-815mV    7.205mA    5.171mA    14.19mA
-611mV    2.275mA    2.213mA    4.254mA
-509mV    589.4uA    929.1uA    1.152mA
-458mV    232.9uA    445.2uA    427.7uA
-254mV    3.785uA    4.472uA    4.114uA
2.5V      0A         0A         3.667nA
[Ramp]
| variable   typ   min   max
dV/dt_r   0.978/0.463n   0.769/0.831n   1.225/0.230n
dV/dt_f   1.052/0.772n   0.801/1.429n   1.263/0.384n
R_load = 50.000
[Rising Waveform]
R_fixture= 50.000
V_fixture= 0.0
V_fixture_min= 0.0
V_fixture_max= 0.0
|time   V(typ)   V(min)   V(max)
0s        4.635nV    35nV       15.53nV
734ps     163uV      -3.75uV    6.126mV
1.114ns   -26.45mV   171.8uV    1.734V
1.349ns   55.5mV     -1.083mV   1.96V
1.595ns   514.4mV    -25.57mV   2.009V
1.922ns   1.255V     -13.93mV   2.03V
2.281ns   1.525V     67.4mV     2.037V
3.34ns    1.622V     1.039V     2.041V
4.343ns   1.629V     1.248V     2.041V
20ns      1.629V     1.281V     2.041V
[Rising Waveform]
R_fixture= 50.000
V_fixture= 2.500
V_fixture_min= 2.380
V_fixture_max= 2.630
|time   V(typ)   V(min)   V(max)
0s        747.2mV    1.044V     524.3mV
538ps     747.2mV    1.044V     540.2mV
682ps     747.3mV    1.044V     1.513V
902ps     759mV      1.044V     2.436V
1.228ns   2.007V     1.045V     2.604V
1.485ns   2.353V     1.11V      2.619V
1.671ns   2.444V     1.75V      2.624V
1.891ns   2.475V     2.107V     2.627V
2.851ns   2.498V     2.36V      2.63V
20ns      2.5V       2.38V      2.63V
[Falling Waveform]
R_fixture= 50.000
V_fixture= 2.500
V_fixture_min= 2.380
V_fixture_max= 2.630
|time   V(typ)   V(min)   V(max)
0s        2.5V       2.38V      2.63V
772ps     2.5V       2.38V      2.635V
1.363ns   2.507V     2.38V      842.7mV
1.519ns   2.377V     2.379V     659.4mV
1.875ns   1.82V      2.439V     559.3mV
2.41ns    1.13V      2.366V     530.9mV
2.911ns   860.1mV    2.087V     526mV
3.993ns   760.6mV    1.424V     524.4mV
5.428ns   748.4mV    1.114V     524.4mV
20ns      747.1mV    1.044V     524.3mV
[Falling Waveform]
R_fixture= 50.000
V_fixture= 0.0
V_fixture_min= 0.0
V_fixture_max= 0.0
|time   V(typ)   V(min)   V(max)
0s        1.629V     1.281V     2.041V
571ps     1.629V     1.281V     2.031V
701ps     1.629V     1.281V     1.159V
923ps     1.632V     1.281V     291.9mV
1.019ns   1.555V     1.281V     103.2mV
1.241ns   625.6mV    1.281V     23.89mV
1.729ns   62.71mV    1.18V      3.668mV
2.127ns   11.96mV    277.5mV    1.1mV
3.003ns   1.47mV     18.75mV    118.1uV
20ns      54.38nV    182.8nV    32.93nV
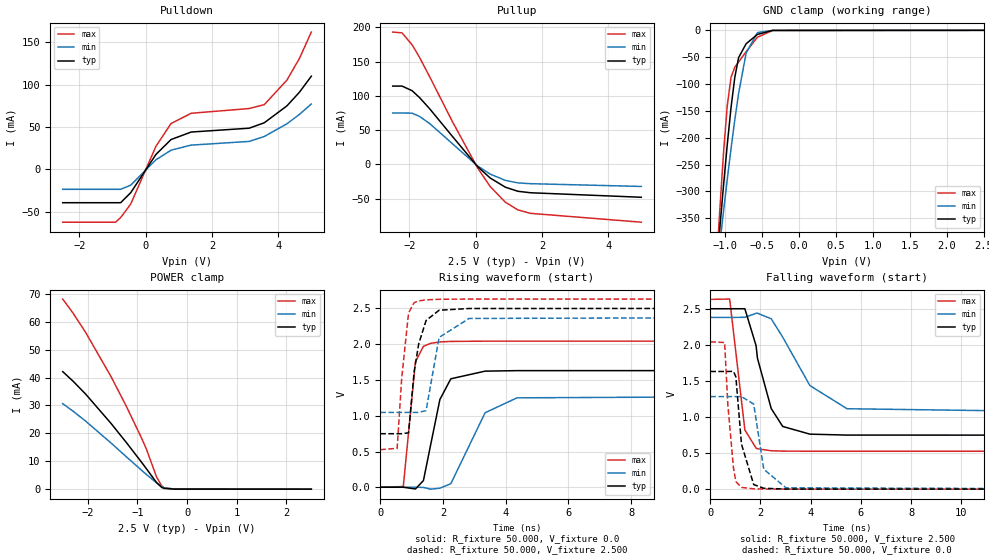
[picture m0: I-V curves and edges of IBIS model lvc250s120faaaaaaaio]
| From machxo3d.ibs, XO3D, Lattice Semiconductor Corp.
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|   Model lvc250s120faaaaaaaio
[Model] lvc250s120faaaaaaaio
Model_type I/O
Polarity   Non-Inverting
Enable   Active-Low
Vinl =  0.700V
Vinh =  1.700V
Vmeas =  1.250V
Cref =  0.0F
Rref =  1.000M
Vref =  0.0V
C_comp   4.200pF   3.800pF   7.500pF
[Temperature Range]   25.000   0.105k   -40.000
[Voltage Range]   2.500V   2.380V   2.630V
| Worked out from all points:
|   slope of the pulldown table from 0 to 0.375 V, typ, clamps not added: 18.1 ohm
|   slope of the pullup table from 0 to 0.375 V, typ, clamps not added: 21.7 ohm
|   GND clamp passes 1 mA (typ) near -0.43 V on its own axis
|   POWER clamp passes 1 mA (typ) near -0.54 V on its own axis
|   rising waveform, R_fixture 50.000, V_fixture 0.0: 20-80 % time 465ps typ, 826ps min, 231ps max; typ from 0.001 V to 1.63 V
|   rising waveform, R_fixture 50.000, V_fixture 2.500: 20-80 % time 343ps typ, 350ps min, 236ps max; typ from 0.749 V to 2.5 V
|   falling waveform, R_fixture 50.000, V_fixture 2.500: 20-80 % time 776ps typ, 1.44ns min, 384ps max; typ from 2.5 V to 0.749 V
|   falling waveform, R_fixture 50.000, V_fixture 0.0: 20-80 % time 356ps typ, 378ps min, 259ps max; typ from 1.63 V to 0.001 V
[Pulldown]
|Voltage   I(typ)   I(min)   I(max)
-2.5V     -39.23mA   -23.44mA   -62.24mA
-904mV    -39.23mA   -23.44mA   -62.24mA
-752mV    -39.23mA   -23.44mA   -56.76mA
-448mV    -27.42mA   -18.49mA   -40.8mA
312mV     17.71mA    11.41mA    27.31mA
768mV     35.33mA    22.74mA    54.24mA
1.376V    44.21mA    28.76mA    66.35mA
3.124V    48.72mA    33.11mA    71.94mA
3.58V     55.12mA    38.9mA     76.53mA
4.264V    75.07mA    53.91mA    105.5mA
4.644V    91.32mA    65.12mA    131.3mA
5V        110.1mA    77.3mA     162.2mA
[Pullup]
|Voltage   I(typ)   I(min)   I(max)
-2.5V     114.2mA    75mA       192.9mA
-2.22V    114.2mA    75mA       191.8mA
-1.916V   107.5mA    74.67mA    174.5mA
-1.688V   97.34mA    69.88mA    155.8mA
-1.384V   81.07mA    59.51mA    127.7mA
-700mV    40.91mA    30.25mA    62.53mA
60mV      -3.106mA   -2.235mA   -5.004mA
440mV     -19.77mA   -14.08mA   -32.21mA
896mV     -33.15mA   -23.24mA   -55.01mA
1.276V    -39.13mA   -26.93mA   -66.27mA
1.656V    -41.29mA   -28.07mA   -71.31mA
5V        -47.88mA   -32.11mA   -84.21mA
[GND_clamp]
|Voltage   I(typ)   I(min)   I(max)
-2.5V     -2.99A     -2.35A     -4.091A
-1.123V   -455.1mA   -463.2mA   -453.7mA
-1.072V   -370.5mA   -399.5mA   -336.3mA
-1.021V   -289.2mA   -337.4mA   -228.6mA
-970mV    -212.6mA   -277.4mA   -140mA
-919mV    -143.6mA   -220.1mA   -87.39mA
-868mV    -87.38mA   -166.5mA   -68.44mA
-817mV    -50.93mA   -117.8mA   -59.12mA
-715mV    -24.98mA   -42.36mA   -39.69mA
-562mV    -7.596mA   -4.111mA   -12.93mA
-358mV    -193.4uA   -101.2uA   -309.3uA
2.5V      13.17nA    0A         -19.29uA
[POWER_clamp]
|Voltage   I(typ)   I(min)   I(max)
-2.5V     42.14mA    30.66mA    68.15mA
-2.294V   38.75mA    27.99mA    63.15mA
-2.039V   34.09mA    24.4mA     56.2mA
-1.529V   23.59mA    16.56mA    40.38mA
-1.223V   16.79mA    11.66mA    29.8mA
-917mV    9.72mA     6.817mA    18.42mA
-815mV    7.285mA    5.246mA    14.27mA
-611mV    2.32mA     2.253mA    4.314mA
-509mV    627.1uA    959.6uA    1.202mA
-458mV    269.3uA    472.4uA    476.3uA
-254mV    28.45uA    20.72uA    43.74uA
2.5V      0A         0A         0A
[Ramp]
| variable   typ   min   max
dV/dt_r   0.978/0.463n   0.769/0.826n   1.224/0.230n
dV/dt_f   1.051/0.774n   0.800/1.426n   1.262/0.386n
R_load = 50.000
[Rising Waveform]
R_fixture= 50.000
V_fixture= 0.0
V_fixture_min= 0.0
V_fixture_max= 0.0
|time   V(typ)   V(min)   V(max)
0s        990.6uV    778.5uV    1.315mV
734ps     1.147mV    773.7uV    10.75mV
1.121ns   -23.33mV   1.064mV    1.753V
1.376ns   94.2mV     -1.753mV   1.97V
1.607ns   594.5mV    -26.06mV   2.012V
1.901ns   1.227V     -12.38mV   2.031V
2.25ns    1.516V     50.68mV    2.038V
3.343ns   1.623V     1.042V     2.042V
4.36ns    1.63V      1.25V      2.042V
20ns      1.631V     1.283V     2.042V
[Rising Waveform]
R_fixture= 50.000
V_fixture= 2.500
V_fixture_min= 2.380
V_fixture_max= 2.630
|time   V(typ)   V(min)   V(max)
0s        748.9mV    1.046V     526.3mV
539ps     748.9mV    1.046V     544.5mV
682ps     749mV      1.046V     1.518V
902ps     760.8mV    1.046V     2.437V
1.08ns    1.615V     1.046V     2.58V
1.226ns   2.005V     1.047V     2.604V
1.461ns   2.331V     1.072V     2.619V
1.876ns   2.474V     2.094V     2.627V
2.831ns   2.498V     2.359V     2.63V
20ns      2.5V       2.38V      2.63V
[Falling Waveform]
R_fixture= 50.000
V_fixture= 2.500
V_fixture_min= 2.380
V_fixture_max= 2.630
|time   V(typ)   V(min)   V(max)
0s        2.5V       2.38V      2.63V
772ps     2.5V       2.38V      2.634V
1.378ns   2.5V       2.381V     821mV
1.824ns   1.989V     2.436V     569.4mV
1.879ns   1.815V     2.438V     561mV
2.427ns   1.118V     2.361V     532.5mV
2.885ns   869.4mV    2.107V     528.1mV
3.968ns   762.9mV    1.436V     526.4mV
5.447ns   749.9mV    1.115V     526.2mV
20ns      748.8mV    1.046V     526.2mV
[Falling Waveform]
R_fixture= 50.000
V_fixture= 0.0
V_fixture_min= 0.0
V_fixture_max= 0.0
|time   V(typ)   V(min)   V(max)
0s        1.631V     1.283V     2.042V
571ps     1.631V     1.283V     2.032V
700ps     1.631V     1.283V     1.168V
923ps     1.633V     1.283V     297.4mV
1.019ns   1.557V     1.283V     106.2mV
1.243ns   624.7mV    1.283V     25.33mV
1.73ns    64.49mV    1.179V     5.374mV
2.131ns   13.12mV    276.5mV    2.407mV
3.013ns   2.499mV    19.57mV    1.425mV
20ns      990.6uV    778.6uV    1.315mV
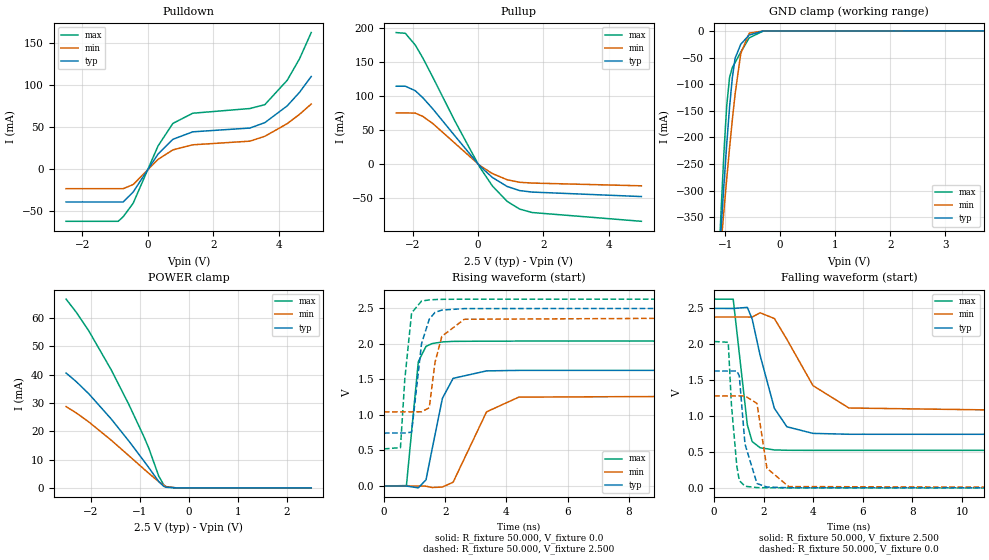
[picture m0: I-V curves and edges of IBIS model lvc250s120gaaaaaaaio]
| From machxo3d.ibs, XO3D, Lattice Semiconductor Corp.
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|   Model lvc250s120gaaaaaaaio
[Model] lvc250s120gaaaaaaaio
Model_type I/O
Polarity   Non-Inverting
Enable   Active-Low
Vinl =  0.700V
Vinh =  1.700V
Vmeas =  1.250V
Cref =  0.0F
Rref =  1.000M
Vref =  0.0V
C_comp   4.200pF   3.800pF   7.500pF
[Temperature Range]   25.000   0.105k   -40.000
[Voltage Range]   2.500V   2.380V   2.630V
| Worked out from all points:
|   slope of the pulldown table from 0 to 0.375 V, typ, clamps not added: 18.1 ohm
|   slope of the pullup table from 0 to 0.375 V, typ, clamps not added: 21.7 ohm
|   GND clamp passes 1 mA (typ) near -0.43 V on its own axis
|   POWER clamp passes 1 mA (typ) near -0.54 V on its own axis
|   rising waveform, R_fixture 50.000, V_fixture 0.0: 20-80 % time 467ps typ, 825ps min, 232ps max; typ from 0 V to 1.63 V
|   rising waveform, R_fixture 50.000, V_fixture 2.500: 20-80 % time 343ps typ, 348ps min, 238ps max; typ from 0.745 V to 2.5 V
|   falling waveform, R_fixture 50.000, V_fixture 2.500: 20-80 % time 769ps typ, 1.44ns min, 383ps max; typ from 2.5 V to 0.745 V
|   falling waveform, R_fixture 50.000, V_fixture 0.0: 20-80 % time 351ps typ, 376ps min, 257ps max; typ from 1.63 V to 0 V
[Pulldown]
|Voltage   I(typ)   I(min)   I(max)
-2.5V     -39.23mA   -23.44mA   -62.24mA
-904mV    -39.23mA   -23.44mA   -62.24mA
-752mV    -39.23mA   -23.44mA   -56.76mA
-448mV    -27.42mA   -18.49mA   -40.8mA
312mV     17.71mA    11.41mA    27.31mA
768mV     35.33mA    22.74mA    54.24mA
1.376V    44.21mA    28.76mA    66.35mA
3.124V    48.71mA    33.11mA    71.94mA
3.58V     55.12mA    38.9mA     76.53mA
4.264V    75.07mA    53.91mA    105.5mA
4.644V    91.33mA    65.11mA    131.3mA
5V        110.1mA    77.29mA    162.3mA
[Pullup]
|Voltage   I(typ)   I(min)   I(max)
-2.5V     114.1mA    74.94mA    192.9mA
-2.22V    114.1mA    74.94mA    191.8mA
-1.916V   107.5mA    74.62mA    174.5mA
-1.688V   97.32mA    69.86mA    155.8mA
-1.384V   81.07mA    59.5mA     127.7mA
-700mV    40.91mA    30.25mA    62.53mA
60mV      -3.106mA   -2.235mA   -5.004mA
440mV     -19.77mA   -14.08mA   -32.21mA
896mV     -33.15mA   -23.24mA   -55.01mA
1.276V    -39.13mA   -26.93mA   -66.27mA
1.656V    -41.29mA   -28.07mA   -71.31mA
5V        -47.88mA   -32.11mA   -84.21mA
[GND_clamp]
|Voltage   I(typ)   I(min)   I(max)
-2.5V     -2.99A     -2.35A     -4.091A
-1.123V   -455.1mA   -463.2mA   -453.7mA
-1.072V   -370.5mA   -399.5mA   -336.3mA
-1.021V   -289.2mA   -337.4mA   -228.6mA
-970mV    -212.6mA   -277.4mA   -140mA
-919mV    -143.6mA   -220.1mA   -87.4mA
-868mV    -87.39mA   -166.5mA   -68.45mA
-817mV    -50.94mA   -117.8mA   -59.13mA
-715mV    -24.99mA   -42.37mA   -39.7mA
-562mV    -7.608mA   -4.125mA   -12.95mA
-307mV    -97.66uA   -51.76uA   -173.8uA
5V        114uA      49.35uA    266.8uA
[POWER_clamp]
|Voltage   I(typ)   I(min)   I(max)
-2.5V     40.55mA    28.7mA     66.64mA
-2.294V   37.53mA    26.47mA    62.05mA
-2.039V   33.25mA    23.31mA    55.5mA
-1.58V    24.33mA    16.84mA    41.69mA
-1.223V   16.6mA     11.41mA    29.54mA
-917mV    9.596mA    6.709mA    18.24mA
-815mV    7.18mA     5.166mA    14.11mA
-611mV    2.243mA    2.205mA    4.167mA
-509mV    558uA      921.7uA    1.059mA
-458mV    208uA      438.7uA    350.8uA
-254mV    2.162uA    3.635uA    1.029uA
2.5V      0A         0A         0A
[Ramp]
| variable   typ   min   max
dV/dt_r   0.976/0.464n   0.768/0.831n   1.223/0.231n
dV/dt_f   1.052/0.771n   0.802/1.426n   1.263/0.383n
R_load = 50.000
[Rising Waveform]
R_fixture= 50.000
V_fixture= 0.0
V_fixture_min= 0.0
V_fixture_max= 0.0
|time   V(typ)   V(min)   V(max)
0s        4.486nV    34.65nV    14.98nV
734ps     161.1uV    -3.769uV   6.454mV
1.122ns   -25.66mV   290.2uV    1.748V
1.374ns   88.05mV    -2.148mV   1.964V
1.574ns   521.2mV    -21.11mV   2.003V
1.909ns   1.233V     -14.09mV   2.026V
2.259ns   1.514V     53.73mV    2.034V
3.351ns   1.619V     1.043V     2.037V
4.404ns   1.626V     1.25V      2.038V
20ns      1.627V     1.28V      2.038V
[Rising Waveform]
R_fixture= 50.000
V_fixture= 2.500
V_fixture_min= 2.380
V_fixture_max= 2.630
|time   V(typ)   V(min)   V(max)
0s        745.3mV    1.043V     522.1mV
539ps     745.3mV    1.043V     539.8mV
682ps     745.4mV    1.043V     1.506V
903ps     758.3mV    1.043V     2.433V
1.228ns   2.002V     1.044V     2.601V
1.481ns   2.347V     1.101V     2.617V
1.667ns   2.441V     1.737V     2.622V
1.891ns   2.474V     2.105V     2.625V
2.626ns   2.495V     2.345V     2.627V
20ns      2.499V     2.379V     2.628V
[Falling Waveform]
R_fixture= 50.000
V_fixture= 2.500
V_fixture_min= 2.380
V_fixture_max= 2.630
|time   V(typ)   V(min)   V(max)
0s        2.499V     2.379V     2.628V
772ps     2.498V     2.379V     2.627V
1.341ns   2.513V     2.379V     876.9mV
1.536ns   2.352V     2.378V     644.9mV
1.856ns   1.846V     2.438V     558.6mV
2.431ns   1.108V     2.358V     528.1mV
2.936ns   850.7mV    2.068V     523.6mV
3.987ns   758.6mV    1.424V     522.1mV
5.437ns   746.3mV    1.112V     522.1mV
20ns      745.3mV    1.043V     522.1mV
[Falling Waveform]
R_fixture= 50.000
V_fixture= 0.0
V_fixture_min= 0.0
V_fixture_max= 0.0
|time   V(typ)   V(min)   V(max)
0s        1.627V     1.28V      2.038V
571ps     1.627V     1.28V      2.027V
701ps     1.627V     1.28V      1.152V
916ps     1.628V     1.28V      306.4mV
1.017ns   1.559V     1.28V      101.8mV
1.246ns   609.7mV    1.28V      22.58mV
1.73ns    61.07mV    1.176V     3.867mV
2.131ns   11.74mV    272.5mV    1.001mV
3.009ns   1.408mV    18.2mV     88.34uV
20ns      49.57nV    178.1nV    24.7nV
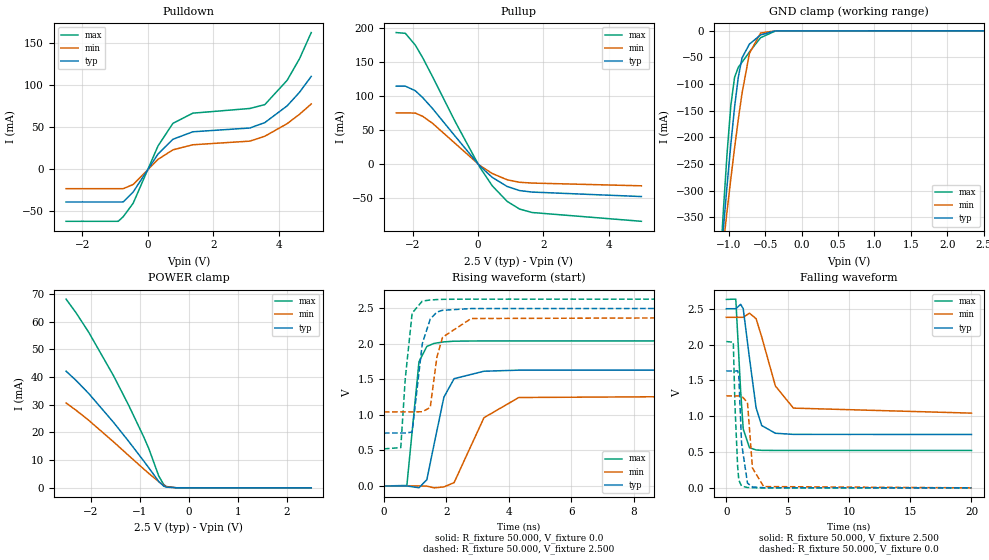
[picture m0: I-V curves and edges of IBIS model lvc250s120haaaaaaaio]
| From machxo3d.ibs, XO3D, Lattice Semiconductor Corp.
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|   Model lvc250s120haaaaaaaio
[Model] lvc250s120haaaaaaaio
Model_type I/O
Polarity   Non-Inverting
Enable   Active-Low
Vinl =  0.700V
Vinh =  1.700V
Vmeas =  1.250V
Cref =  0.0F
Rref =  1.000M
Vref =  0.0V
C_comp   4.200pF   3.800pF   7.500pF
[Temperature Range]   25.000   0.105k   -40.000
[Voltage Range]   2.500V   2.380V   2.630V
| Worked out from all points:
|   slope of the pulldown table from 0 to 0.375 V, typ, clamps not added: 18.1 ohm
|   slope of the pullup table from 0 to 0.375 V, typ, clamps not added: 21.7 ohm
|   GND clamp passes 1 mA (typ) near -0.43 V on its own axis
|   POWER clamp passes 1 mA (typ) near -0.54 V on its own axis
|   rising waveform, R_fixture 50.000, V_fixture 0.0: 20-80 % time 467ps typ, 829ps min, 233ps max; typ from 0 V to 1.63 V
|   rising waveform, R_fixture 50.000, V_fixture 2.500: 20-80 % time 343ps typ, 351ps min, 239ps max; typ from 0.745 V to 2.5 V
|   falling waveform, R_fixture 50.000, V_fixture 2.500: 20-80 % time 774ps typ, 1.44ns min, 385ps max; typ from 2.5 V to 0.745 V
|   falling waveform, R_fixture 50.000, V_fixture 0.0: 20-80 % time 360ps typ, 381ps min, 260ps max; typ from 1.63 V to 0 V
[Pulldown]
|Voltage   I(typ)   I(min)   I(max)
-2.5V     -39.23mA   -23.44mA   -62.24mA
-904mV    -39.23mA   -23.44mA   -62.24mA
-752mV    -39.23mA   -23.44mA   -56.76mA
-448mV    -27.42mA   -18.49mA   -40.8mA
312mV     17.71mA    11.41mA    27.31mA
768mV     35.33mA    22.74mA    54.24mA
1.376V    44.21mA    28.76mA    66.35mA
3.124V    48.72mA    33.11mA    71.94mA
3.58V     55.12mA    38.9mA     76.53mA
4.264V    75.07mA    53.91mA    105.5mA
4.644V    91.32mA    65.12mA    131.3mA
5V        110.1mA    77.3mA     162.2mA
[Pullup]
|Voltage   I(typ)   I(min)   I(max)
-2.5V     114.2mA    75mA       192.9mA
-2.22V    114.2mA    75mA       191.8mA
-1.916V   107.5mA    74.67mA    174.5mA
-1.688V   97.34mA    69.88mA    155.8mA
-1.384V   81.07mA    59.51mA    127.7mA
-700mV    40.91mA    30.25mA    62.53mA
60mV      -3.106mA   -2.235mA   -5.004mA
440mV     -19.77mA   -14.08mA   -32.21mA
896mV     -33.15mA   -23.24mA   -55.01mA
1.276V    -39.13mA   -26.93mA   -66.27mA
1.656V    -41.29mA   -28.07mA   -71.31mA
5V        -47.88mA   -32.11mA   -84.21mA
[GND_clamp]
|Voltage   I(typ)   I(min)   I(max)
-2.5V     -2.99A     -2.35A     -4.091A
-1.123V   -455.1mA   -463.2mA   -453.7mA
-1.072V   -370.5mA   -399.5mA   -336.3mA
-1.021V   -289.2mA   -337.4mA   -228.6mA
-970mV    -212.6mA   -277.4mA   -140mA
-919mV    -143.6mA   -220.1mA   -87.4mA
-868mV    -87.39mA   -166.5mA   -68.45mA
-817mV    -50.94mA   -117.8mA   -59.13mA
-715mV    -24.99mA   -42.37mA   -39.7mA
-562mV    -7.608mA   -4.125mA   -12.95mA
-358mV    -194.9uA   -98.36uA   -303.6uA
2.5V      13.17nA    0A         -19.29uA
[POWER_clamp]
|Voltage   I(typ)   I(min)   I(max)
-2.5V     42.14mA    30.66mA    68.15mA
-2.294V   38.75mA    27.99mA    63.15mA
-2.039V   34.09mA    24.4mA     56.2mA
-1.529V   23.59mA    16.56mA    40.38mA
-1.223V   16.79mA    11.66mA    29.8mA
-917mV    9.72mA     6.817mA    18.42mA
-815mV    7.285mA    5.246mA    14.27mA
-611mV    2.32mA     2.253mA    4.314mA
-509mV    627.1uA    959.6uA    1.202mA
-458mV    269.3uA    472.4uA    476.3uA
-254mV    28.45uA    20.72uA    43.74uA
2.5V      0A         0A         0A
[Ramp]
| variable   typ   min   max
dV/dt_r   0.979/0.467n   0.770/0.833n   1.225/0.232n
dV/dt_f   1.053/0.777n   0.802/1.439n   1.265/0.387n
R_load = 50.000
[Rising Waveform]
R_fixture= 50.000
V_fixture= 0.0
V_fixture_min= 0.0
V_fixture_max= 0.0
|time   V(typ)   V(min)   V(max)
0s        4.486nV    34.65nV    14.98nV
734ps     161.1uV    -3.791uV   6.454mV
1.122ns   -25.66mV   290.5uV    1.748V
1.374ns   88.05mV    -2.208mV   1.964V
1.605ns   584.8mV    -26.88mV   2.007V
1.921ns   1.25V      -13.77mV   2.028V
2.247ns   1.51V      46.83mV    2.038V
3.204ns   1.615V     960.8mV    2.042V
4.32ns    1.63V      1.245V     2.042V
20ns      1.631V     1.283V     2.042V
[Rising Waveform]
R_fixture= 50.000
V_fixture= 2.500
V_fixture_min= 2.380
V_fixture_max= 2.630
|time   V(typ)   V(min)   V(max)
0s        745.3mV    1.043V     522.1mV
539ps     745.3mV    1.043V     539.8mV
682ps     745.4mV    1.043V     1.506V
903ps     758.3mV    1.043V     2.433V
1.228ns   2.002V     1.044V     2.602V
1.483ns   2.349V     1.105V     2.618V
1.697ns   2.448V     1.816V     2.624V
1.879ns   2.473V     2.094V     2.627V
2.795ns   2.497V     2.357V     2.63V
20ns      2.5V       2.38V      2.63V
[Falling Waveform]
R_fixture= 50.000
V_fixture= 2.500
V_fixture_min= 2.380
V_fixture_max= 2.630
|time   V(typ)   V(min)   V(max)
0s        2.5V       2.38V      2.63V
772ps     2.5V       2.38V      2.634V
1.169ns   2.561V     2.38V      1.348V
1.378ns   2.5V       2.381V     821mV
1.886ns   1.815V     2.438V     560.2mV
2.427ns   1.118V     2.361V     528.8mV
2.885ns   869.4mV    2.107V     523.9mV
4.004ns   762mV      1.421V     522.1mV
5.471ns   746.4mV    1.113V     522.1mV
20ns      745.3mV    1.043V     522mV
[Falling Waveform]
R_fixture= 50.000
V_fixture= 0.0
V_fixture_min= 0.0
V_fixture_max= 0.0
|time   V(typ)   V(min)   V(max)
0s        1.631V     1.283V     2.042V
571ps     1.631V     1.283V     2.032V
700ps     1.631V     1.283V     1.168V
923ps     1.633V     1.283V     297.4mV
1.019ns   1.557V     1.283V     106.2mV
1.243ns   624.7mV    1.283V     25.33mV
1.725ns   66.3mV     1.191V     4.431mV
2.131ns   13.19mV    276.5mV    1.054mV
3.041ns   1.63mV     18.13mV    104.5uV
20ns      47.96nV    177.4nV    22.99nV
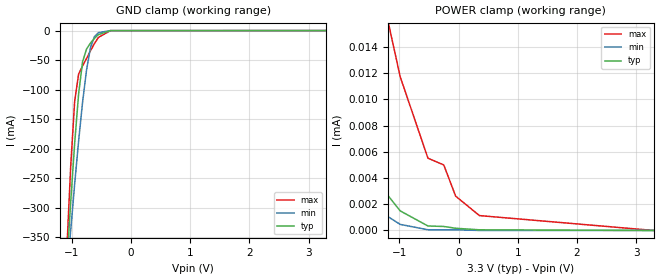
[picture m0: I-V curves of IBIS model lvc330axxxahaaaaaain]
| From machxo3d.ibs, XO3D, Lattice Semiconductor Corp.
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|   Model lvc330axxxahaaaaaain
[Model] lvc330axxxahaaaaaain
Model_type Input
Polarity   Non-Inverting
Enable   Active-High
Vinl =  0.800V
Vinh =  2.000V
C_comp   4.200pF   3.800pF   7.500pF
[Temperature Range]   25.000   0.105k   -40.000
[Voltage Range]   3.300V   3.140V   3.470V
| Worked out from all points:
|   GND clamp passes 1 mA (typ) near -0.43 V on its own axis
[GND_clamp]
|Voltage   I(typ)   I(min)   I(max)
-3.3V     -4.507A    -3.482A    -6.263A
-1.089V   -398.4mA   -420.6mA   -374.6mA
-1.022V   -290.6mA   -338.6mA   -230.5mA
-955mV    -191.3mA   -260.2mA   -120mA
-888mV    -107.4mA   -187mA     -73.59mA
-821mV    -52.93mA   -121.4mA   -59.73mA
-754mV    -31.33mA   -66.91mA   -47.35mA
-687mV    -21.09mA   -28.78mA   -34.13mA
-620mV    -13.14mA   -10.18mA   -21.88mA
-553mV    -6.797mA   -3.527mA   -11.6mA
-352mV    -94.79uA   -46.13uA   -137.4uA
3.3V      0A         0A         0A
[POWER_clamp]
|Voltage   I(typ)   I(min)   I(max)
-3.3V     732.2uA    455.9uA    1.265mA
-2.663V   69.44uA    15.46uA    306.8uA
-2.529V   27.69uA    10.95uA    164.1uA
-2.328V   15.69uA    8.498uA    64.68uA
-1.725V   7.348uA    3.694uA    30.69uA
-1.189V   2.632uA    1.04uA     15.85uA
-988mV    1.494uA    463.1nA    11.72uA
-519mV    342.8nA    54.82nA    5.51uA
-251mV    305.1nA    47.69nA    4.994uA
-50mV     169nA      47.69nA    2.616uA
352mV     50.68nA    4.172nA    1.135uA
3.3V      0A         0A         0A
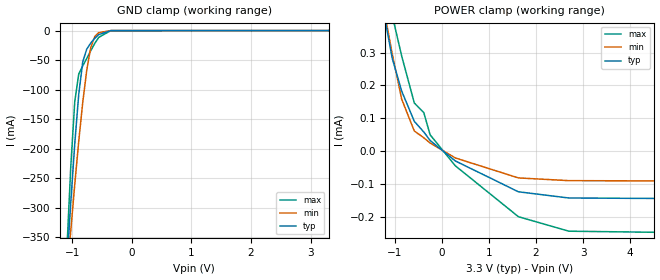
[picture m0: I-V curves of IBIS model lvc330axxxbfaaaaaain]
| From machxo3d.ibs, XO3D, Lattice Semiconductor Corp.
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|   Model lvc330axxxbfaaaaaain
[Model] lvc330axxxbfaaaaaain
Model_type Input
Polarity   Non-Inverting
Enable   Active-High
Vinl =  0.800V
Vinh =  2.000V
C_comp   4.200pF   3.800pF   7.500pF
[Temperature Range]   25.000   0.105k   -40.000
[Voltage Range]   3.300V   3.140V   3.470V
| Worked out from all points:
|   GND clamp passes 1 mA (typ) near -0.43 V on its own axis
|   POWER clamp passes 1 mA (typ) near -1.85 V on its own axis
[GND_clamp]
|Voltage   I(typ)   I(min)   I(max)
-3.3V     -4.506A    -3.482A    -6.262A
-1.089V   -398.3mA   -420.5mA   -374.5mA
-1.022V   -290.6mA   -338.5mA   -230.4mA
-955mV    -191.2mA   -260.1mA   -119.8mA
-888mV    -107.4mA   -186.9mA   -73.47mA
-821mV    -52.87mA   -121.3mA   -59.62mA
-754mV    -31.28mA   -66.86mA   -47.24mA
-687mV    -21.04mA   -28.74mA   -34.02mA
-620mV    -13.09mA   -10.15mA   -21.79mA
-553mV    -6.755mA   -3.505mA   -11.52mA
-352mV    -90.18uA   -45.39uA   -119.9uA
3.3V      0A         0A         0A
[POWER_clamp]
|Voltage   I(typ)   I(min)   I(max)
-3.3V     3.967mA    2.512mA    11.53mA
-1.323V   507.3uA    506.4uA    605.6uA
-1.189V   387.7uA    399.8uA    501.1uA
-1.055V   282.8uA    296.7uA    413.8uA
-854mV    182.6uA    158.2uA    289.7uA
-586mV    90.73uA    61.33uA    146.6uA
-385mV    58.36uA    40.66uA    117.5uA
-251mV    32.53uA    24.74uA    49.87uA
285mV     -29.95uA   -20.85uA   -44.72uA
1.625V    -124uA     -81.72uA   -199.9uA
2.697V    -142.9uA   -90.03uA   -244.1uA
6.6V      -145.9uA   -91.75uA   -251.2uA
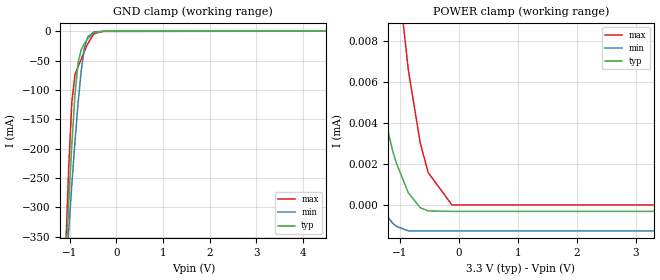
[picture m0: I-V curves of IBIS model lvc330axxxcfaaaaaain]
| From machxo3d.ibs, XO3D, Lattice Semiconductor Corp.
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|   Model lvc330axxxcfaaaaaain
[Model] lvc330axxxcfaaaaaain
Model_type Input
Polarity   Non-Inverting
Enable   Active-High
Vinl =  0.800V
Vinh =  2.000V
C_comp   4.200pF   3.800pF   7.500pF
[Temperature Range]   25.000   0.105k   -40.000
[Voltage Range]   3.300V   3.140V   3.470V
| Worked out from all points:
|   GND clamp passes 1 mA (typ) near -0.43 V on its own axis
[GND_clamp]
|Voltage   I(typ)   I(min)   I(max)
-3.3V     -4.507A    -3.482A    -6.263A
-1.089V   -398.4mA   -420.6mA   -374.7mA
-1.022V   -290.7mA   -338.6mA   -230.6mA
-955mV    -191.4mA   -260.2mA   -120.1mA
-888mV    -107.5mA   -187mA     -73.7mA
-821mV    -53mA      -121.4mA   -59.85mA
-754mV    -31.41mA   -66.94mA   -47.47mA
-687mV    -21.17mA   -28.82mA   -34.25mA
-620mV    -13.21mA   -10.23mA   -22mA
-486mV    -2.63mA    -1.112mA   -4.479mA
-285mV    -80.91uA   -42.41uA   -152.3uA
6.6V      121.2uA    55.82uA    291.2uA
[POWER_clamp]
|Voltage   I(typ)   I(min)   I(max)
-3.3V     704.7uA    440.9uA    1.167mA
-2.596V   46.79uA    12.42uA    184.2uA
-2.328V   25.67uA    8.107uA    76.87uA
-1.792V   13.09uA    2.762uA    43.68uA
-1.39V    5.98uA     124.1nA    24.26uA
-1.122V   2.656uA    -886.1nA   13.98uA
-1.055V   2.02uA     -1.042uA   11.85uA
-854mV    585.6nA    -1.267uA   6.557uA
-653mV    -133.8nA   -1.267uA   3.017uA
-519mV    -290.6nA   -1.267uA   1.58uA
-117mV    -313.6nA   -1.267uA   0A
3.3V      -313.6nA   -1.267uA   0A
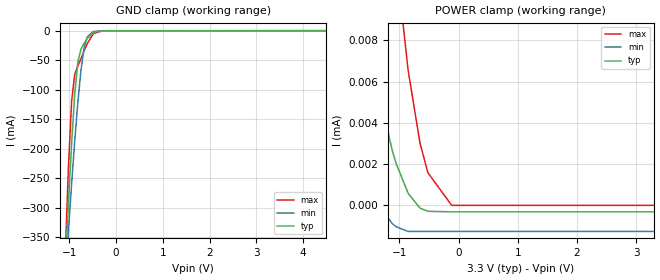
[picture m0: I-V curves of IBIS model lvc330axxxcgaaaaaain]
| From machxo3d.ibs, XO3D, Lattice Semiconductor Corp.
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|   Model lvc330axxxcgaaaaaain
[Model] lvc330axxxcgaaaaaain
Model_type Input
Polarity   Non-Inverting
Enable   Active-High
Vinl =  0.800V
Vinh =  2.000V
C_comp   4.200pF   3.800pF   7.500pF
[Temperature Range]   25.000   0.105k   -40.000
[Voltage Range]   3.300V   3.140V   3.470V
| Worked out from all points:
|   GND clamp passes 1 mA (typ) near -0.43 V on its own axis
[GND_clamp]
|Voltage   I(typ)   I(min)   I(max)
-3.3V     -4.507A    -3.482A    -6.263A
-1.089V   -398.4mA   -420.6mA   -374.7mA
-1.022V   -290.7mA   -338.6mA   -230.6mA
-955mV    -191.3mA   -260.2mA   -120mA
-888mV    -107.5mA   -187mA     -73.68mA
-821mV    -52.99mA   -121.4mA   -59.82mA
-754mV    -31.39mA   -66.94mA   -47.44mA
-687mV    -21.15mA   -28.82mA   -34.22mA
-620mV    -13.2mA    -10.23mA   -21.98mA
-486mV    -2.625mA   -1.111mA   -4.467mA
-285mV    -80.85uA   -42.41uA   -152uA
6.6V      121.2uA    55.81uA    291.2uA
[POWER_clamp]
|Voltage   I(typ)   I(min)   I(max)
-3.3V     704.7uA    440.9uA    1.167mA
-2.596V   46.79uA    12.42uA    184.2uA
-2.328V   25.67uA    8.112uA    76.87uA
-1.792V   13.09uA    2.766uA    43.68uA
-1.39V    5.981uA    126.6nA    24.26uA
-1.122V   2.657uA    -884.1nA   13.98uA
-1.055V   2.02uA     -1.04uA    11.85uA
-854mV    586nA      -1.266uA   6.557uA
-653mV    -133.6nA   -1.266uA   3.018uA
-519mV    -290.4nA   -1.266uA   1.58uA
-117mV    -313.4nA   -1.266uA   0A
3.3V      -313.4nA   -1.266uA   0A
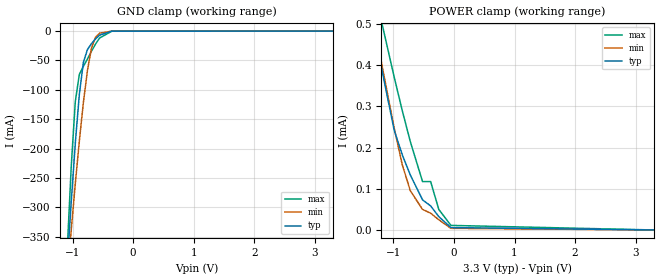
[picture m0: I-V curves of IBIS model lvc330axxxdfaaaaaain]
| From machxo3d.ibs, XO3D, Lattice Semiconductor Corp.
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|   Model lvc330axxxdfaaaaaain
[Model] lvc330axxxdfaaaaaain
Model_type Input
Polarity   Non-Inverting
Enable   Active-High
Vinl =  0.800V
Vinh =  2.000V
C_comp   4.200pF   3.800pF   7.500pF
[Temperature Range]   25.000   0.105k   -40.000
[Voltage Range]   3.300V   3.140V   3.470V
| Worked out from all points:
|   GND clamp passes 1 mA (typ) near -0.43 V on its own axis
|   POWER clamp passes 1 mA (typ) near -1.85 V on its own axis
[GND_clamp]
|Voltage   I(typ)   I(min)   I(max)
-3.3V     -4.507A    -3.482A    -6.263A
-1.089V   -398.4mA   -420.6mA   -374.7mA
-1.022V   -290.7mA   -338.6mA   -230.6mA
-955mV    -191.4mA   -260.2mA   -120.1mA
-888mV    -107.5mA   -187mA     -73.7mA
-821mV    -53mA      -121.4mA   -59.85mA
-754mV    -31.41mA   -66.94mA   -47.47mA
-687mV    -21.17mA   -28.82mA   -34.25mA
-620mV    -13.21mA   -10.23mA   -22mA
-553mV    -6.875mA   -3.578mA   -11.73mA
-352mV    -176.3uA   -89.98uA   -279uA
3.3V      50.87nA    0A         -26.43uA
[POWER_clamp]
|Voltage   I(typ)   I(min)   I(max)
-3.3V     3.967mA    2.512mA    11.53mA
-1.323V   507.3uA    506.4uA    605.6uA
-1.256V   446.6uA    452.8uA    548.7uA
-1.189V   387.7uA    399.8uA    501.1uA
-988mV    242.5uA    247.5uA    371.4uA
-854mV    182.6uA    158.2uA    289.7uA
-720mV    133.1uA    94.82uA    213.9uA
-519mV    73.06uA    49.89uA    117.5uA
-385mV    58.36uA    40.66uA    117.5uA
-251mV    32.53uA    24.74uA    49.87uA
-50mV     5.761uA    3.987uA    11.09uA
3.3V      0A         0A         0A
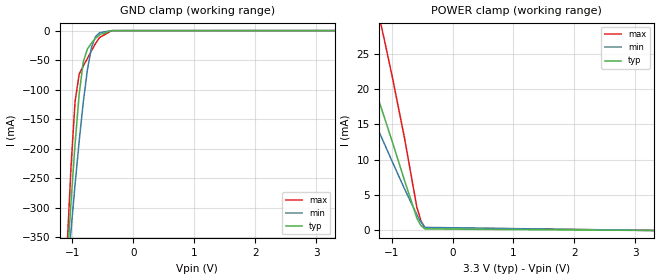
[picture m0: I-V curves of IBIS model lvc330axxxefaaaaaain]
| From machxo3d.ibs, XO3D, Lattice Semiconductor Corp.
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|   Model lvc330axxxefaaaaaain
[Model] lvc330axxxefaaaaaain
Model_type Input
Polarity   Non-Inverting
Enable   Active-High
Vinl =  0.800V
Vinh =  2.000V
C_comp   4.200pF   3.800pF   7.500pF
[Temperature Range]   25.000   0.105k   -40.000
[Voltage Range]   3.300V   3.140V   3.470V
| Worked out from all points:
|   GND clamp passes 1 mA (typ) near -0.43 V on its own axis
|   POWER clamp passes 1 mA (typ) near -0.54 V on its own axis
[GND_clamp]
|Voltage   I(typ)   I(min)   I(max)
-3.3V     -4.507A    -3.482A    -6.263A
-1.089V   -398.4mA   -420.6mA   -374.7mA
-1.022V   -290.7mA   -338.6mA   -230.6mA
-955mV    -191.3mA   -260.2mA   -120mA
-888mV    -107.5mA   -187mA     -73.64mA
-821mV    -52.96mA   -121.4mA   -59.79mA
-754mV    -31.36mA   -66.92mA   -47.4mA
-687mV    -21.12mA   -28.79mA   -34.18mA
-620mV    -13.16mA   -10.19mA   -21.93mA
-553mV    -6.814mA   -3.53mA    -11.64mA
-352mV    -96.36uA   -46.21uA   -149.8uA
3.3V      0A         0A         0A
[POWER_clamp]
|Voltage   I(typ)   I(min)   I(max)
-3.3V     59.07mA    46.89mA    89.53mA
-1.993V   37.2mA     28.86mA    58.21mA
-1.926V   35.72mA    27.66mA    56.06mA
-1.591V   27.93mA    21.43mA    44.68mA
-1.189V   17.86mA    13.66mA    29.77mA
-1.122V   16.11mA    12.35mA    27.14mA
-988mV    12.56mA    9.745mA    21.76mA
-787mV    7.078mA    5.887mA    13.07mA
-586mV    1.773mA    2.247mA    3.338mA
-519mV    707uA      1.205mA    1.383mA
-452mV    214.8uA    435.5uA    392.3uA
3.3V      0A         0A         0A
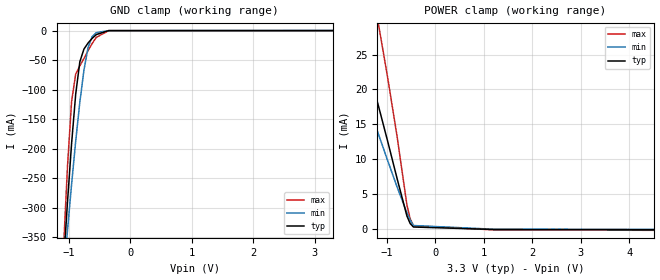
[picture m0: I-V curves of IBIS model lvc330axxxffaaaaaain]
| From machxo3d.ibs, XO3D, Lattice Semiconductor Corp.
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|   Model lvc330axxxffaaaaaain
[Model] lvc330axxxffaaaaaain
Model_type Input
Polarity   Non-Inverting
Enable   Active-High
Vinl =  0.800V
Vinh =  2.000V
C_comp   4.200pF   3.800pF   7.500pF
[Temperature Range]   25.000   0.105k   -40.000
[Voltage Range]   3.300V   3.140V   3.470V
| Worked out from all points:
|   GND clamp passes 1 mA (typ) near -0.43 V on its own axis
|   POWER clamp passes 1 mA (typ) near -0.53 V on its own axis
[GND_clamp]
|Voltage   I(typ)   I(min)   I(max)
-3.3V     -4.506A    -3.482A    -6.262A
-1.089V   -398.3mA   -420.5mA   -374.5mA
-1.022V   -290.6mA   -338.5mA   -230.4mA
-955mV    -191.2mA   -260.1mA   -119.8mA
-888mV    -107.4mA   -186.9mA   -73.47mA
-821mV    -52.87mA   -121.3mA   -59.62mA
-754mV    -31.28mA   -66.86mA   -47.24mA
-687mV    -21.04mA   -28.74mA   -34.02mA
-620mV    -13.09mA   -10.15mA   -21.79mA
-553mV    -6.755mA   -3.505mA   -11.52mA
-352mV    -90.18uA   -45.39uA   -119.9uA
3.3V      0A         0A         0A
[POWER_clamp]
|Voltage   I(typ)   I(min)   I(max)
-3.3V     62.1mA     51.02mA    92.7mA
-1.926V   36.35mA    28.59mA    56.55mA
-1.591V   28.28mA    21.98mA    45.01mA
-1.189V   18.03mA    13.9mA     29.96mA
-1.122V   16.26mA    12.55mA    27.31mA
-988mV    12.68mA    9.882mA    21.88mA
-787mV    7.154mA    5.963mA    13.15mA
-586mV    1.819mA    2.29mA     3.395mA
-519mV    748.7uA    1.242mA    1.434mA
-452mV    255.4uA    468.1uA    442.9uA
1.223V    -104.1uA   -69.89uA   -164.8uA
6.6V      -145.9uA   -91.75uA   -251.2uA
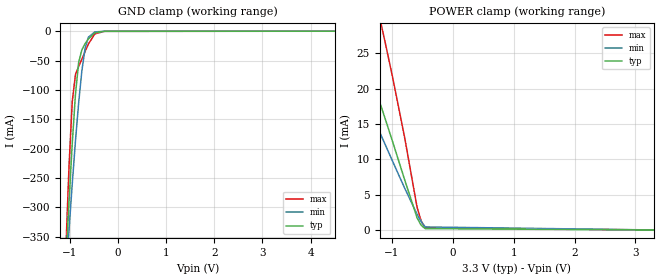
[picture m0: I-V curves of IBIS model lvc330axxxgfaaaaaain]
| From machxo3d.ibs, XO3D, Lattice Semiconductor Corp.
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|   Model lvc330axxxgfaaaaaain
[Model] lvc330axxxgfaaaaaain
Model_type Input
Polarity   Non-Inverting
Enable   Active-High
Vinl =  0.800V
Vinh =  2.000V
C_comp   4.200pF   3.800pF   7.500pF
[Temperature Range]   25.000   0.105k   -40.000
[Voltage Range]   3.300V   3.140V   3.470V
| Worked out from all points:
|   GND clamp passes 1 mA (typ) near -0.43 V on its own axis
|   POWER clamp passes 1 mA (typ) near -0.54 V on its own axis
[GND_clamp]
|Voltage   I(typ)   I(min)   I(max)
-3.3V     -4.507A    -3.482A    -6.263A
-1.089V   -398.4mA   -420.6mA   -374.7mA
-1.022V   -290.7mA   -338.6mA   -230.6mA
-955mV    -191.4mA   -260.2mA   -120.1mA
-888mV    -107.5mA   -187mA     -73.7mA
-821mV    -53mA      -121.4mA   -59.85mA
-754mV    -31.41mA   -66.94mA   -47.47mA
-687mV    -21.17mA   -28.82mA   -34.25mA
-620mV    -13.21mA   -10.23mA   -22mA
-486mV    -2.63mA    -1.112mA   -4.479mA
-285mV    -80.91uA   -42.41uA   -152.3uA
6.6V      121.2uA    55.84uA    291.2uA
[POWER_clamp]
|Voltage   I(typ)   I(min)   I(max)
-3.3V     59.17mA    46.96mA    89.71mA
-1.993V   37.21mA    28.87mA    58.18mA
-1.926V   35.73mA    27.67mA    56.02mA
-1.591V   27.93mA    21.43mA    44.63mA
-1.189V   17.84mA    13.65mA    29.69mA
-1.122V   16.09mA    12.35mA    27.06mA
-988mV    12.53mA    9.74mA     21.66mA
-787mV    7.047mA    5.88mA     12.98mA
-586mV    1.736mA    2.238mA    3.233mA
-519mV    672uA      1.196mA    1.278mA
-452mV    189uA      428.3uA    309.6uA
3.3V      0A         0A         0A
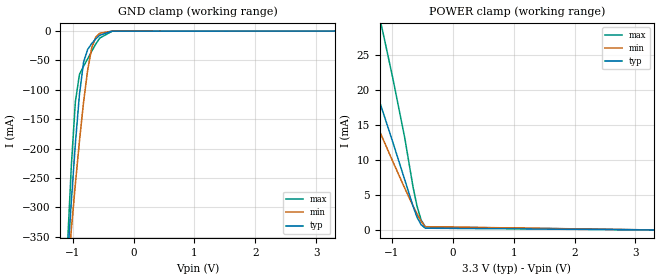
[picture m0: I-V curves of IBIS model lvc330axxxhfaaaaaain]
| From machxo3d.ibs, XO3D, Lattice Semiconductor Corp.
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|   Model lvc330axxxhfaaaaaain
[Model] lvc330axxxhfaaaaaain
Model_type Input
Polarity   Non-Inverting
Enable   Active-High
Vinl =  0.800V
Vinh =  2.000V
C_comp   4.200pF   3.800pF   7.500pF
[Temperature Range]   25.000   0.105k   -40.000
[Voltage Range]   3.300V   3.140V   3.470V
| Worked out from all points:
|   GND clamp passes 1 mA (typ) near -0.43 V on its own axis
|   POWER clamp passes 1 mA (typ) near -0.53 V on its own axis
[GND_clamp]
|Voltage   I(typ)   I(min)   I(max)
-3.3V     -4.507A    -3.482A    -6.263A
-1.089V   -398.4mA   -420.6mA   -374.7mA
-1.022V   -290.7mA   -338.6mA   -230.6mA
-955mV    -191.4mA   -260.2mA   -120.1mA
-888mV    -107.5mA   -187mA     -73.7mA
-821mV    -53mA      -121.4mA   -59.85mA
-754mV    -31.41mA   -66.94mA   -47.47mA
-687mV    -21.17mA   -28.82mA   -34.25mA
-620mV    -13.21mA   -10.23mA   -22mA
-553mV    -6.875mA   -3.578mA   -11.73mA
-352mV    -176.3uA   -89.98uA   -279uA
3.3V      50.87nA    0A         -26.43uA
[POWER_clamp]
|Voltage   I(typ)   I(min)   I(max)
-3.3V     62.1mA     51.02mA    92.7mA
-1.926V   36.35mA    28.59mA    56.55mA
-1.591V   28.28mA    21.98mA    45.01mA
-1.189V   18.03mA    13.9mA     29.96mA
-1.122V   16.26mA    12.55mA    27.31mA
-988mV    12.68mA    9.882mA    21.88mA
-787mV    7.154mA    5.963mA    13.15mA
-653mV    3.439mA    3.462mA    6.207mA
-586mV    1.819mA    2.29mA     3.395mA
-519mV    748.7uA    1.242mA    1.434mA
-452mV    255.4uA    468.1uA    442.9uA
3.3V      0A         0A         0A
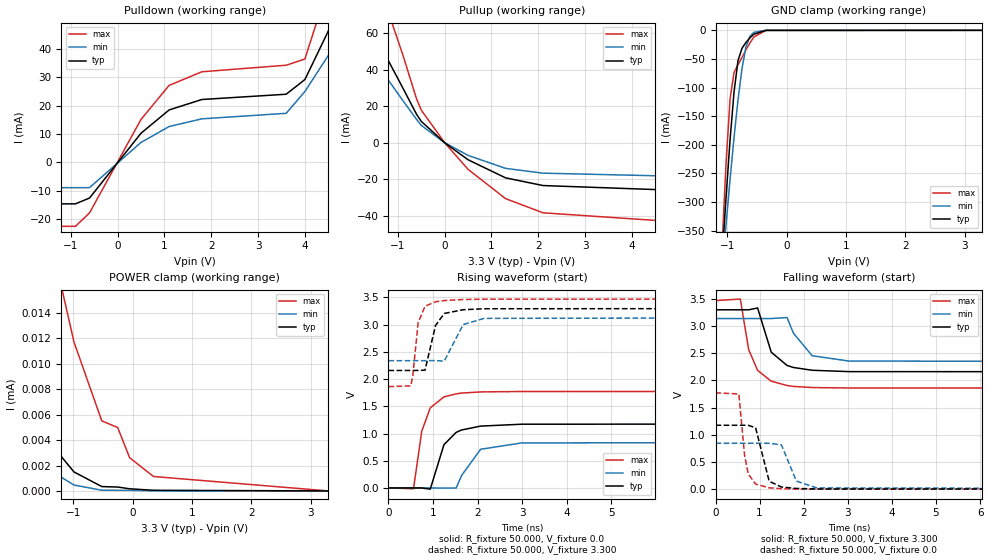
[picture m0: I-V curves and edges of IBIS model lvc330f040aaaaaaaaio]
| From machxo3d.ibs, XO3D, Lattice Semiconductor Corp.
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|   Model lvc330f040aaaaaaaaio
[Model] lvc330f040aaaaaaaaio
Model_type I/O
Polarity   Non-Inverting
Enable   Active-Low
Vinl =  0.800V
Vinh =  2.000V
Vmeas =  1.650V
Cref =  0.0F
Rref =  1.000M
Vref =  0.0V
C_comp   4.200pF   3.800pF   7.500pF
[Temperature Range]   25.000   0.105k   -40.000
[Voltage Range]   3.300V   3.140V   3.470V
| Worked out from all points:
|   slope of the pulldown table from 0 to 0.495 V, typ, clamps not added: 48.6 ohm
|   slope of the pullup table from 0 to 0.495 V, typ, clamps not added: 53.4 ohm
|   GND clamp passes 1 mA (typ) near -0.43 V on its own axis
|   rising waveform, R_fixture 50.000, V_fixture 0.0: 20-80 % time 344ps typ, 378ps min, 271ps max; typ from 0 V to 1.18 V
|   rising waveform, R_fixture 50.000, V_fixture 3.300: 20-80 % time 198ps typ, 272ps min, 136ps max; typ from 2.16 V to 3.3 V
|   falling waveform, R_fixture 50.000, V_fixture 3.300: 20-80 % time 345ps typ, 358ps min, 326ps max; typ from 3.3 V to 2.16 V
|   falling waveform, R_fixture 50.000, V_fixture 0.0: 20-80 % time 184ps typ, 246ps min, 137ps max; typ from 1.18 V to 0 V
[Pulldown]
|Voltage   I(typ)   I(min)   I(max)
-3.3V     -14.66mA   -8.951mA   -22.6mA
-900mV    -14.66mA   -8.951mA   -22.6mA
-600mV    -12.62mA   -8.951mA   -17.88mA
500mV     10.27mA    7.01mA     15.14mA
1.1V      18.49mA    12.63mA    27.15mA
1.8V      22.18mA    15.35mA    31.97mA
3.6V      24.04mA    17.3mA     34.28mA
4V        29.22mA    25mA       36.49mA
4.6V      49.78mA    40.29mA    67.41mA
5V        65.22mA    51.84mA    90.99mA
5.5V      86.65mA    67.52mA    124.4mA
6.6V      140.3mA    103.4mA    210.9mA
[Pullup]
|Voltage   I(typ)   I(min)   I(max)
-3.3V     135mA      102.2mA    210.2mA
-2.8V     116.4mA    88.68mA    183.7mA
-2.4V     99.85mA    76.1mA     157.6mA
-1.3V     49.65mA    37.77mA    78.79mA
-900mV    30.33mA    23.37mA    48.67mA
-600mV    15.55mA    12.76mA    24mA
-500mV    11.71mA    9.507mA    17.89mA
0V        40fA       1.018pA    300fA
500mV     -9.346mA   -6.955mA   -14.59mA
1.3V      -19.24mA   -14.05mA   -30.62mA
2.1V      -23.46mA   -16.68mA   -38.39mA
6.6V      -27.59mA   -19.35mA   -46.21mA
[GND_clamp]
|Voltage   I(typ)   I(min)   I(max)
-3.3V     -4.507A    -3.482A    -6.263A
-1.089V   -398.4mA   -420.6mA   -374.7mA
-1.022V   -290.7mA   -338.6mA   -230.6mA
-955mV    -191.3mA   -260.2mA   -120mA
-888mV    -107.5mA   -187mA     -73.64mA
-821mV    -52.96mA   -121.4mA   -59.79mA
-754mV    -31.36mA   -66.92mA   -47.4mA
-687mV    -21.12mA   -28.79mA   -34.18mA
-620mV    -13.16mA   -10.19mA   -21.93mA
-553mV    -6.814mA   -3.53mA    -11.64mA
-352mV    -96.36uA   -46.21uA   -149.8uA
3.3V      0A         0A         0A
[POWER_clamp]
|Voltage   I(typ)   I(min)   I(max)
-3.3V     732.2uA    455.9uA    1.265mA
-2.663V   69.44uA    15.46uA    306.8uA
-2.529V   27.69uA    10.95uA    164.1uA
-2.328V   15.69uA    8.497uA    64.68uA
-1.725V   7.348uA    3.693uA    30.69uA
-1.189V   2.632uA    1.04uA     15.85uA
-988mV    1.494uA    463.1nA    11.72uA
-519mV    342.8nA    54.75nA    5.51uA
-251mV    305.1nA    47.63nA    4.994uA
-50mV     169nA      47.63nA    2.616uA
352mV     50.67nA    4.149nA    1.135uA
3.3V      0A         0A         0A
[Ramp]
| variable   typ   min   max
dV/dt_r   0.705/0.347n   0.507/0.376n   1.064/0.271n
dV/dt_f   0.685/0.344n   0.481/0.362n   0.965/0.324n
R_load = 50.000
[Rising Waveform]
R_fixture= 50.000
V_fixture= 0.0
V_fixture_min= 0.0
V_fixture_max= 0.0
|time   V(typ)   V(min)   V(max)
0s        27.69nV    65.53nV    348nV
562ps     50.04uV    29.7uV     -14.85mV
747ps     200.3uV    -1.372uV   1.041V
938ps     -22.47mV   119.6uV    1.471V
1.246ns   795.2mV    -2.287mV   1.673V
1.52ns    1.021V     -1.648mV   1.728V
1.642ns   1.065V     229mV      1.743V
2.07ns    1.136V     710.9mV    1.764V
2.997ns   1.171V     827.2mV    1.772V
20ns      1.176V     844.4mV    1.773V
[Rising Waveform]
R_fixture= 50.000
V_fixture= 3.300
V_fixture_min= 3.140
V_fixture_max= 3.470
|time   V(typ)   V(min)   V(max)
0s        2.158V     2.338V     1.861V
502ps     2.158V     2.338V     1.875V
547ps     2.158V     2.338V     2.068V
666ps     2.159V     2.338V     3.034V
821ps     2.164V     2.338V     3.339V
1.056ns   2.982V     2.34V      3.42V
1.252ns   3.205V     2.33V      3.443V
1.678ns   3.274V     3.002V     3.462V
2.147ns   3.292V     3.115V     3.468V
20ns      3.3V       3.14V      3.47V
[Falling Waveform]
R_fixture= 50.000
V_fixture= 3.300
V_fixture_min= 3.140
V_fixture_max= 3.470
|time   V(typ)   V(min)   V(max)
0s        3.3V       3.14V      3.47V
563ps     3.3V       3.14V      3.498V
751ps     3.3V       3.14V      2.569V
954ps     3.334V     3.14V      2.186V
1.263ns   2.521V     3.14V      1.987V
1.621ns   2.277V     3.158V     1.907V
1.767ns   2.239V     2.87V      1.891V
2.191ns   2.188V     2.455V     1.87V
3.027ns   2.163V     2.357V     1.862V
20ns      2.158V     2.338V     1.861V
[Falling Waveform]
R_fixture= 50.000
V_fixture= 0.0
V_fixture_min= 0.0
V_fixture_max= 0.0
|time   V(typ)   V(min)   V(max)
0s        1.176V     844.4mV    1.773V
529ps     1.176V     844.3mV    1.752V
659ps     1.176V     844.3mV    621.5mV
742ps     1.175V     844.5mV    281.3mV
909ps     1.13V      844.5mV    93.36mV
1.217ns   145.1mV    844mV      24.8mV
1.494ns   40.13mV    815.7mV    9.129mV
1.833ns   13.04mV    149mV      2.906mV
2.297ns   3.556mV    22.31mV    575.2uV
20ns      -94.92nV   130.1nV    139.1nV
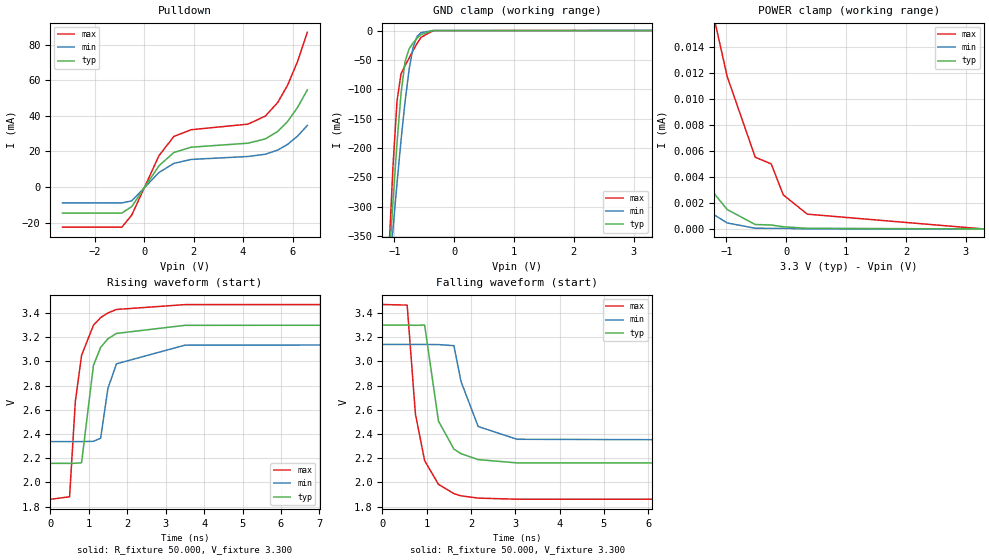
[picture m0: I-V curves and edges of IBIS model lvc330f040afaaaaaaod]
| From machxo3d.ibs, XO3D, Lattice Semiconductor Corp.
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|   Model lvc330f040afaaaaaaod
[Model] lvc330f040afaaaaaaod
Model_type I/O_open_drain
Polarity   Non-Inverting
Enable   Active-Low
Vinl =  0.800V
Vinh =  2.000V
Vmeas =  1.650V
Cref =  0.0F
Rref = 10.00k
Vref = 3.30V
C_comp   4.200pF   3.800pF   7.500pF
[Temperature Range]   25.000   0.105k   -40.000
[Voltage Range]   3.300V   3.140V   3.470V
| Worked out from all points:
|   slope of the pulldown table from 0 to 0.495 V, typ, clamps not added: 48.6 ohm
|   GND clamp passes 1 mA (typ) near -0.43 V on its own axis
|   rising waveform, R_fixture 50.000, V_fixture 3.300: 20-80 % time 337ps typ, 340ps min, 336ps max; typ from 2.16 V to 3.3 V
|   falling waveform, R_fixture 50.000, V_fixture 3.300: 20-80 % time 339ps typ, 371ps min, 326ps max; typ from 3.3 V to 2.16 V
[Pulldown]
|Voltage   I(typ)   I(min)   I(max)
-3.3V     -14.66mA   -8.951mA   -22.6mA
-900mV    -14.66mA   -8.951mA   -22.6mA
-500mV    -11.02mA   -7.807mA   -15.8mA
600mV     11.95mA    8.157mA    17.61mA
1.2V      19.4mA     13.27mA    28.41mA
1.9V      22.39mA    15.51mA    32.23mA
4.2V      24.66mA    17.16mA    35.37mA
4.9V      27.05mA    18.44mA    39.88mA
5.4V      31.26mA    20.77mA    47.51mA
5.8V      36.84mA    23.96mA    57.23mA
6.2V      44.67mA    28.59mA    70.48mA
6.6V      54.65mA    34.63mA    87.04mA
[GND_clamp]
|Voltage   I(typ)   I(min)   I(max)
-3.3V     -4.507A    -3.482A    -6.263A
-1.089V   -398.4mA   -420.6mA   -374.7mA
-1.022V   -290.7mA   -338.6mA   -230.6mA
-955mV    -191.3mA   -260.2mA   -120mA
-888mV    -107.5mA   -187mA     -73.64mA
-821mV    -52.96mA   -121.4mA   -59.79mA
-754mV    -31.36mA   -66.92mA   -47.4mA
-687mV    -21.12mA   -28.79mA   -34.18mA
-620mV    -13.16mA   -10.19mA   -21.93mA
-553mV    -6.814mA   -3.53mA    -11.64mA
-352mV    -96.36uA   -46.21uA   -149.8uA
3.3V      0A         0A         0A
[POWER_clamp]
|Voltage   I(typ)   I(min)   I(max)
-3.3V     732.2uA    455.9uA    1.265mA
-2.663V   69.44uA    15.46uA    306.8uA
-2.529V   27.69uA    10.95uA    164.1uA
-2.328V   15.69uA    8.497uA    64.68uA
-1.725V   7.348uA    3.693uA    30.69uA
-1.189V   2.632uA    1.04uA     15.85uA
-988mV    1.494uA    463nA      11.72uA
-519mV    342.8nA    54.74nA    5.51uA
-251mV    305.1nA    47.62nA    4.994uA
-50mV     169nA      47.62nA    2.616uA
352mV     50.67nA    4.149nA    1.135uA
3.3V      0A         0A         0A
[Ramp]
| variable   typ   min   max
dV/dt_r   0.685/0.336n   0.481/0.341n   0.965/0.335n
dV/dt_f   0.685/0.346n   0.481/0.372n   0.965/0.325n
R_load = 50.000
[Rising Waveform]
R_fixture= 50.000
V_fixture= 3.300
V_fixture_min= 3.140
V_fixture_max= 3.470
|time   V(typ)   V(min)   V(max)
0s        2.158V     2.338V     1.861V
502ps     2.158V     2.338V     1.882V
652ps     2.159V     2.338V     2.67V
814ps     2.163V     2.338V     3.05V
1.123ns   2.968V     2.34V      3.299V
1.31ns    3.116V     2.366V     3.362V
1.499ns   3.187V     2.777V     3.4V
1.721ns   3.231V     2.98V      3.429V
3.502ns   3.298V     3.134V     3.469V
20ns      3.3V       3.14V      3.47V
[Falling Waveform]
R_fixture= 50.000
V_fixture= 3.300
V_fixture_min= 3.140
V_fixture_max= 3.470
|time   V(typ)   V(min)   V(max)
0s        3.3V       3.14V      3.47V
560ps     3.3V       3.14V      3.465V
746ps     3.298V     3.14V      2.566V
954ps     3.3V       3.14V      2.18V
1.266ns   2.508V     3.139V     1.985V
1.615ns   2.276V     3.13V      1.908V
1.776ns   2.238V     2.833V     1.89V
2.163ns   2.189V     2.462V     1.871V
3.039ns   2.162V     2.357V     1.862V
20ns      2.158V     2.338V     1.861V
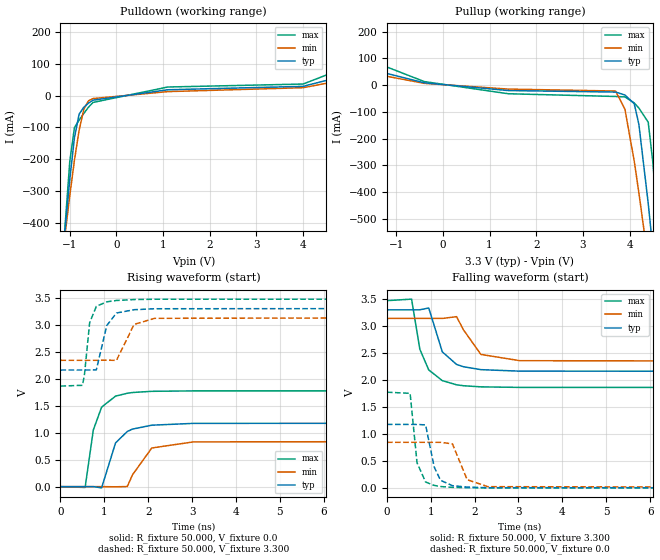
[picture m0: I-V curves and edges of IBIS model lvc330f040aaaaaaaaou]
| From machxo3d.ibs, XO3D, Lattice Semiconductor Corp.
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|   Model lvc330f040aaaaaaaaou
[Model] lvc330f040aaaaaaaaou
Model_type Output
Polarity   Non-Inverting
Enable   Active-High
Vmeas =  1.650V
Cref =  0.0F
Rref =  1.000M
Vref =  0.0V
C_comp   4.200pF   3.800pF   7.500pF
[Temperature Range]   25.000   0.105k   -40.000
[Voltage Range]   3.300V   3.140V   3.470V
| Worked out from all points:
|   slope of the pulldown table from 0 to 0.495 V, typ, clamps not added: 48.6 ohm
|   slope of the pullup table from 0 to 0.495 V, typ, clamps not added: 53.4 ohm
|   rising waveform, R_fixture 50.000, V_fixture 0.0: 20-80 % time 344ps typ, 380ps min, 271ps max; typ from 0 V to 1.18 V
|   rising waveform, R_fixture 50.000, V_fixture 3.300: 20-80 % time 198ps typ, 272ps min, 135ps max; typ from 2.16 V to 3.3 V
|   falling waveform, R_fixture 50.000, V_fixture 3.300: 20-80 % time 345ps typ, 361ps min, 325ps max; typ from 3.3 V to 2.16 V
|   falling waveform, R_fixture 50.000, V_fixture 0.0: 20-80 % time 184ps typ, 246ps min, 137ps max; typ from 1.18 V to 0 V
[Pulldown]
|Voltage   I(typ)   I(min)   I(max)
-3.3V     -4.507A    -3.482A    -6.263A
-1.1V     -420mA     -435.9mA   -408.3mA
-1V       -263.3mA   -314.6mA   -207mA
-900mV    -132.6mA   -203.2mA   -100.5mA
-800mV    -58.22mA   -109.1mA   -77.24mA
-700mV    -36.75mA   -43.32mA   -56.27mA
-600mV    -23.7mA    -16.39mA   -36.49mA
-500mV    -14.27mA   -9.199mA   -21.38mA
1.1V      18.49mA    12.63mA    27.15mA
4V        29.22mA    25mA       36.5mA
5.3V      77.81mA    61.11mA    110.5mA
6.6V      141mA      104.1mA    211.9mA
[Pullup]
|Voltage   I(typ)   I(min)   I(max)
-3.3V     135.7mA    102.7mA    211.4mA
-400mV    8.948mA    6.927mA    13.59mA
1.4V      -20.07mA   -14.6mA    -32.02mA
3.7V      -25.75mA   -21.88mA   -42.22mA
3.9V      -36.65mA   -89.28mA   -43.81mA
4.1V      -69.34mA   -284.1mA   -66.52mA
4.2V      -146.7mA   -403mA     -85.68mA
4.4V      -442.7mA   -658.2mA   -138.5mA
4.5V      -613.1mA   -790.6mA   -290.1mA
4.6V      -789.1mA   -924.9mA   -514mA
4.7V      -968.5mA   -1.061A    -759.1mA
6.6V      -4.534A    -3.729A    -5.846A
[Ramp]
| variable   typ   min   max
dV/dt_r   0.705/0.347n   0.507/0.376n   1.064/0.271n
dV/dt_f   0.685/0.344n   0.481/0.362n   0.965/0.324n
R_load = 50.000
[Rising Waveform]
R_fixture= 50.000
V_fixture= 0.0
V_fixture_min= 0.0
V_fixture_max= 0.0
|time   V(typ)   V(min)   V(max)
0s        27.69nV    65.53nV    348nV
562ps     45.08uV    26.56uV    -14.84mV
749ps     163.9uV    -3.933uV   1.049V
938ps     -22.47mV   97.02uV    1.471V
1.255ns   808.2mV    -2.877mV   1.675V
1.524ns   1.021V     1.99mV     1.728V
1.642ns   1.065V     219.8mV    1.742V
2.082ns   1.137V     715.5mV    1.764V
3.031ns   1.171V     828.2mV    1.772V
20ns      1.176V     844.4mV    1.773V
[Rising Waveform]
R_fixture= 50.000
V_fixture= 3.300
V_fixture_min= 3.140
V_fixture_max= 3.470
|time   V(typ)   V(min)   V(max)
0s        2.158V     2.338V     1.861V
502ps     2.158V     2.338V     1.875V
547ps     2.158V     2.338V     2.068V
666ps     2.159V     2.338V     3.034V
818ps     2.161V     2.338V     3.337V
1.056ns   2.982V     2.34V      3.42V
1.277ns   3.213V     2.337V     3.445V
1.678ns   3.274V     3.002V     3.462V
2.147ns   3.292V     3.115V     3.468V
20ns      3.3V       3.14V      3.47V
[Falling Waveform]
R_fixture= 50.000
V_fixture= 3.300
V_fixture_min= 3.140
V_fixture_max= 3.470
|time   V(typ)   V(min)   V(max)
0s        3.3V       3.14V      3.47V
563ps     3.3V       3.14V      3.498V
751ps     3.3V       3.14V      2.569V
954ps     3.334V     3.14V      2.186V
1.263ns   2.521V     3.14V      1.987V
1.589ns   2.287V     3.173V     1.91V
1.741ns   2.246V     2.934V     1.893V
2.143ns   2.191V     2.473V     1.872V
3.032ns   2.163V     2.357V     1.862V
20ns      2.158V     2.338V     1.861V
[Falling Waveform]
R_fixture= 50.000
V_fixture= 0.0
V_fixture_min= 0.0
V_fixture_max= 0.0
|time   V(typ)   V(min)   V(max)
0s        1.176V     844.4mV    1.773V
529ps     1.176V     844.4mV    1.752V
687ps     1.175V     844.4mV    465.5mV
882ps     1.167V     844.5mV    108.5mV
1.079ns   385.7mV    844.4mV    45.02mV
1.223ns   139.9mV    844.1mV    24.76mV
1.494ns   40.3mV     815.7mV    9.018mV
1.83ns    13.9mV     151.5mV    2.86mV
2.3ns     3.587mV    22.13mV    556.4uV
20ns      -187.8nV   129.1nV    116.1nV
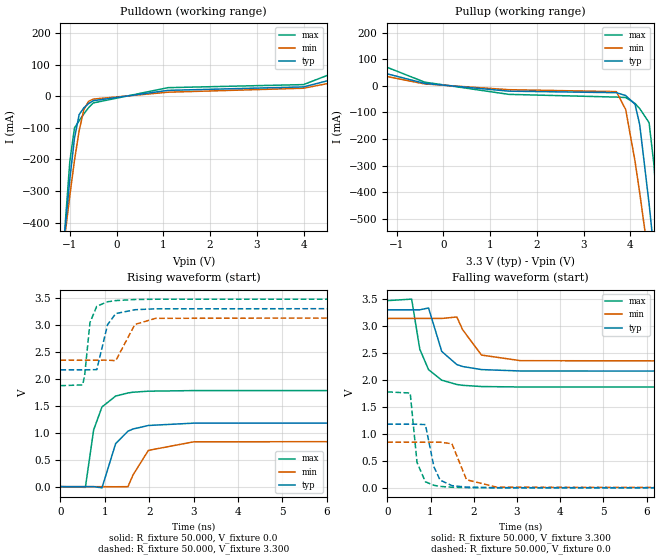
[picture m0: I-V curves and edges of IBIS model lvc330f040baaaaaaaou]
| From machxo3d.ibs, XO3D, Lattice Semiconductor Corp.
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|   Model lvc330f040baaaaaaaou
[Model] lvc330f040baaaaaaaou
Model_type Output
Polarity   Non-Inverting
Enable   Active-High
Vmeas =  1.650V
Cref =  0.0F
Rref =  1.000M
Vref =  0.0V
C_comp   4.200pF   3.800pF   7.500pF
[Temperature Range]   25.000   0.105k   -40.000
[Voltage Range]   3.300V   3.140V   3.470V
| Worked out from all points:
|   slope of the pulldown table from 0 to 0.495 V, typ, clamps not added: 48.6 ohm
|   slope of the pullup table from 0 to 0.495 V, typ, clamps not added: 53.2 ohm
|   rising waveform, R_fixture 50.000, V_fixture 0.0: 20-80 % time 342ps typ, 379ps min, 270ps max; typ from 0.003 V to 1.18 V
|   rising waveform, R_fixture 50.000, V_fixture 3.300: 20-80 % time 199ps typ, 273ps min, 135ps max; typ from 2.16 V to 3.3 V
|   falling waveform, R_fixture 50.000, V_fixture 3.300: 20-80 % time 343ps typ, 364ps min, 324ps max; typ from 3.3 V to 2.16 V
|   falling waveform, R_fixture 50.000, V_fixture 0.0: 20-80 % time 184ps typ, 246ps min, 137ps max; typ from 1.18 V to 0.003 V
[Pulldown]
|Voltage   I(typ)   I(min)   I(max)
-3.3V     -4.507A    -3.482A    -6.263A
-1.1V     -420mA     -435.9mA   -408.3mA
-1V       -263.3mA   -314.6mA   -207.1mA
-900mV    -132.7mA   -203.2mA   -100.5mA
-800mV    -58.28mA   -109.1mA   -77.32mA
-700mV    -36.82mA   -43.36mA   -56.37mA
-600mV    -23.77mA   -16.45mA   -36.61mA
-500mV    -14.37mA   -9.275mA   -21.53mA
1.1V      18.35mA    12.55mA    26.91mA
4V        29.28mA    25.1mA     36.55mA
5.3V      78.51mA    62.37mA    111mA
6.6V      144mA      108.8mA    214.5mA
[Pullup]
|Voltage   I(typ)   I(min)   I(max)
-3.3V     138.8mA    106.8mA    214.6mA
-400mV    8.988mA    6.957mA    13.64mA
1.4V      -20.18mA   -14.68mA   -32.2mA
3.7V      -25.88mA   -21.94mA   -42.46mA
3.9V      -36.73mA   -89.31mA   -43.99mA
4.1V      -69.39mA   -284.1mA   -66.62mA
4.2V      -146.7mA   -403mA     -85.76mA
4.4V      -442.8mA   -658.2mA   -138.5mA
4.5V      -613.1mA   -790.6mA   -290.2mA
4.6V      -789.1mA   -924.9mA   -514mA
4.7V      -968.6mA   -1.061A    -759.2mA
6.6V      -4.534A    -3.729A    -5.846A
[Ramp]
| variable   typ   min   max
dV/dt_r   0.707/0.346n   0.508/0.376n   1.065/0.270n
dV/dt_f   0.682/0.343n   0.480/0.362n   0.960/0.323n
R_load = 50.000
[Rising Waveform]
R_fixture= 50.000
V_fixture= 0.0
V_fixture_min= 0.0
V_fixture_max= 0.0
|time   V(typ)   V(min)   V(max)
0s        3.283mV    2.496mV    4.478mV
562ps     3.328mV    2.521mV    -9.747mV
747ps     3.471mV    2.491mV    1.05V
936ps     -19.44mV   2.561mV    1.477V
1.243ns   797mV      750.7uV    1.678V
1.521ns   1.028V     2.609mV    1.735V
1.637ns   1.069V     221.4mV    1.749V
1.981ns   1.134V     673.3mV    1.768V
3.002ns   1.177V     831.6mV    1.779V
20ns      1.182V     848.7mV    1.78V
[Rising Waveform]
R_fixture= 50.000
V_fixture= 3.300
V_fixture_min= 3.140
V_fixture_max= 3.470
|time   V(typ)   V(min)   V(max)
0s        2.163V     2.341V     1.87V
502ps     2.163V     2.341V     1.884V
547ps     2.163V     2.341V     2.077V
666ps     2.164V     2.341V     3.039V
819ps     2.167V     2.341V     3.339V
1.062ns   2.998V     2.342V     3.421V
1.246ns   3.203V     2.332V     3.443V
1.678ns   3.274V     3.002V     3.463V
2.145ns   3.291V     3.115V     3.468V
20ns      3.3V       3.14V      3.47V
[Falling Waveform]
R_fixture= 50.000
V_fixture= 3.300
V_fixture_min= 3.140
V_fixture_max= 3.470
|time   V(typ)   V(min)   V(max)
0s        3.3V       3.14V      3.47V
563ps     3.3V       3.14V      3.498V
751ps     3.3V       3.14V      2.571V
954ps     3.334V     3.14V      2.191V
1.259ns   2.529V     3.14V      1.997V
1.608ns   2.286V     3.167V     1.917V
1.741ns   2.25V      2.934V     1.902V
2.178ns   2.193V     2.462V     1.879V
3.082ns   2.167V     2.358V     1.871V
20ns      2.163V     2.341V     1.87V
[Falling Waveform]
R_fixture= 50.000
V_fixture= 0.0
V_fixture_min= 0.0
V_fixture_max= 0.0
|time   V(typ)   V(min)   V(max)
0s        1.182V     848.7mV    1.78V
529ps     1.182V     848.6mV    1.759V
687ps     1.181V     848.6mV    472.8mV
881ps     1.174V     848.7mV    114.3mV
1.079ns   390.9mV    848.6mV    49.78mV
1.221ns   145.8mV    848.4mV    29.6mV
1.494ns   43.82mV    820mV      13.76mV
1.833ns   16.57mV    152.1mV    7.118mV
2.538ns   5.207mV    14.17mV    4.825mV
20ns      3.283mV    2.496mV    4.477mV
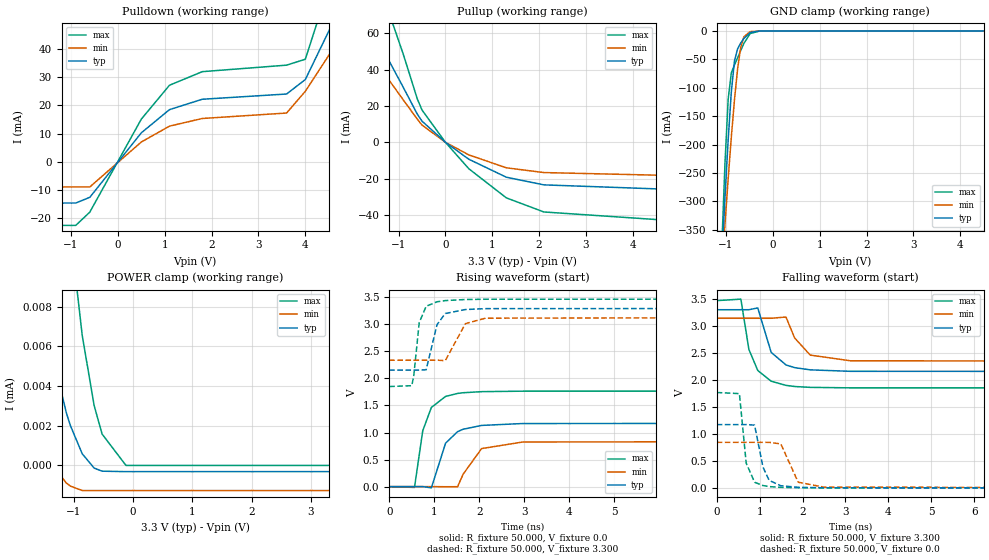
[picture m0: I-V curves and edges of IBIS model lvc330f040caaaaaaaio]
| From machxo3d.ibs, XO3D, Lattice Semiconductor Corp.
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|   Model lvc330f040caaaaaaaio
[Model] lvc330f040caaaaaaaio
Model_type I/O
Polarity   Non-Inverting
Enable   Active-Low
Vinl =  0.800V
Vinh =  2.000V
Vmeas =  1.650V
Cref =  0.0F
Rref =  1.000M
Vref =  0.0V
C_comp   4.200pF   3.800pF   7.500pF
[Temperature Range]   25.000   0.105k   -40.000
[Voltage Range]   3.300V   3.140V   3.470V
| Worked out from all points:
|   slope of the pulldown table from 0 to 0.495 V, typ, clamps not added: 48.6 ohm
|   slope of the pullup table from 0 to 0.495 V, typ, clamps not added: 53.4 ohm
|   GND clamp passes 1 mA (typ) near -0.43 V on its own axis
|   rising waveform, R_fixture 50.000, V_fixture 0.0: 20-80 % time 344ps typ, 383ps min, 271ps max; typ from 0 V to 1.17 V
|   rising waveform, R_fixture 50.000, V_fixture 3.300: 20-80 % time 199ps typ, 272ps min, 136ps max; typ from 2.15 V to 3.3 V
|   falling waveform, R_fixture 50.000, V_fixture 3.300: 20-80 % time 344ps typ, 362ps min, 324ps max; typ from 3.3 V to 2.15 V
|   falling waveform, R_fixture 50.000, V_fixture 0.0: 20-80 % time 183ps typ, 245ps min, 136ps max; typ from 1.17 V to 0 V
[Pulldown]
|Voltage   I(typ)   I(min)   I(max)
-3.3V     -14.66mA   -8.951mA   -22.6mA
-900mV    -14.66mA   -8.951mA   -22.6mA
-600mV    -12.62mA   -8.951mA   -17.88mA
500mV     10.27mA    7.01mA     15.14mA
1.1V      18.49mA    12.63mA    27.15mA
1.8V      22.18mA    15.35mA    31.97mA
3.6V      24.04mA    17.29mA    34.28mA
4V        29.18mA    25mA       36.39mA
4.6V      49.76mA    40.29mA    67.32mA
5V        65.22mA    51.85mA    90.92mA
5.5V      86.66mA    67.54mA    124.4mA
6.6V      140.4mA    103.5mA    211.2mA
[Pullup]
|Voltage   I(typ)   I(min)   I(max)
-3.3V     135.1mA    102.3mA    210.5mA
-2.9V     120.4mA    91.65mA    189.6mA
-2.5V     104.1mA    79.37mA    164.5mA
-1.4V     54.37mA    41.37mA    86.06mA
-900mV    30.3mA     23.37mA    48.57mA
-600mV    15.51mA    12.76mA    23.9mA
-500mV    11.68mA    9.5mA      17.79mA
0V        0A         0A         0A
500mV     -9.346mA   -6.955mA   -14.59mA
1.3V      -19.24mA   -14.05mA   -30.62mA
2.1V      -23.46mA   -16.68mA   -38.39mA
6.6V      -27.59mA   -19.35mA   -46.21mA
[GND_clamp]
|Voltage   I(typ)   I(min)   I(max)
-3.3V     -4.507A    -3.482A    -6.263A
-1.089V   -398.4mA   -420.6mA   -374.7mA
-1.022V   -290.7mA   -338.6mA   -230.6mA
-955mV    -191.4mA   -260.2mA   -120.1mA
-888mV    -107.5mA   -187mA     -73.7mA
-821mV    -53mA      -121.4mA   -59.85mA
-754mV    -31.41mA   -66.94mA   -47.47mA
-687mV    -21.17mA   -28.82mA   -34.25mA
-620mV    -13.21mA   -10.23mA   -22mA
-486mV    -2.63mA    -1.112mA   -4.479mA
-285mV    -80.91uA   -42.41uA   -152.3uA
6.6V      121.2uA    55.82uA    291.2uA
[POWER_clamp]
|Voltage   I(typ)   I(min)   I(max)
-3.3V     704.7uA    440.9uA    1.167mA
-2.596V   46.79uA    12.42uA    184.2uA
-2.328V   25.67uA    8.107uA    76.87uA
-1.792V   13.09uA    2.762uA    43.68uA
-1.39V    5.98uA     124nA      24.26uA
-1.122V   2.656uA    -886.2nA   13.98uA
-1.055V   2.02uA     -1.042uA   11.85uA
-854mV    585.7nA    -1.267uA   6.557uA
-653mV    -133.8nA   -1.267uA   3.017uA
-519mV    -290.6nA   -1.267uA   1.58uA
-117mV    -313.6nA   -1.267uA   0A
3.3V      -313.6nA   -1.267uA   0A
[Ramp]
| variable   typ   min   max
dV/dt_r   0.703/0.346n   0.506/0.376n   1.059/0.271n
dV/dt_f   0.687/0.344n   0.481/0.362n   0.969/0.323n
R_load = 50.000
[Rising Waveform]
R_fixture= 50.000
V_fixture= 0.0
V_fixture_min= 0.0
V_fixture_max= 0.0
|time   V(typ)   V(min)   V(max)
0s        27.06nV    64.78nV    334.4nV
562ps     49.87uV    29.64uV    -14.81mV
746ps     194.4uV    -1.429uV   1.034V
937ps     -22.94mV   119.5uV    1.463V
1.253ns   803.4mV    -2.289mV   1.667V
1.52ns    1.016V     -1.614mV   1.722V
1.642ns   1.06V      229mV      1.735V
2.053ns   1.131V     703mV      1.755V
2.967ns   1.166V     824.4mV    1.764V
20ns      1.171V     842.7mV    1.765V
[Rising Waveform]
R_fixture= 50.000
V_fixture= 3.300
V_fixture_min= 3.140
V_fixture_max= 3.470
|time   V(typ)   V(min)   V(max)
0s        2.153V     2.336V     1.85V
502ps     2.153V     2.336V     1.865V
547ps     2.153V     2.336V     2.056V
667ps     2.154V     2.336V     3.03V
821ps     2.159V     2.336V     3.333V
1.062ns   2.992V     2.338V     3.416V
1.245ns   3.199V     2.327V     3.438V
1.693ns   3.273V     3.012V     3.458V
2.139ns   3.289V     3.113V     3.463V
20ns      3.297V     3.139V     3.465V
[Falling Waveform]
R_fixture= 50.000
V_fixture= 3.300
V_fixture_min= 3.140
V_fixture_max= 3.470
|time   V(typ)   V(min)   V(max)
0s        3.297V     3.139V     3.465V
563ps     3.297V     3.139V     3.493V
750ps     3.297V     3.139V     2.562V
957ps     3.33V      3.139V     2.172V
1.269ns   2.508V     3.139V     1.974V
1.614ns   2.275V     3.162V     1.897V
1.815ns   2.225V     2.775V     1.876V
2.179ns   2.184V     2.457V     1.86V
3.111ns   2.157V     2.352V     1.851V
20ns      2.153V     2.336V     1.85V
[Falling Waveform]
R_fixture= 50.000
V_fixture= 0.0
V_fixture_min= 0.0
V_fixture_max= 0.0
|time   V(typ)   V(min)   V(max)
0s        1.171V     842.7mV    1.765V
529ps     1.171V     842.6mV    1.744V
687ps     1.171V     842.8mV    458.7mV
883ps     1.161V     842.8mV    104mV
1.078ns   385.3mV    842.6mV    42.77mV
1.221ns   139.3mV    842.4mV    23.71mV
1.494ns   39.27mV    814mV      9.088mV
1.898ns   10.56mV    104.6mV    2.205mV
2.504ns   2.006mV    12.49mV    314.4uV
20ns      -87.82nV   118.4nV    155.5nV
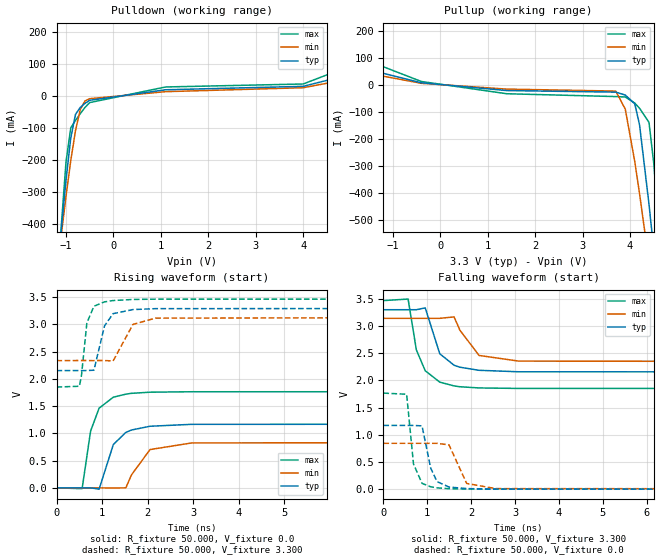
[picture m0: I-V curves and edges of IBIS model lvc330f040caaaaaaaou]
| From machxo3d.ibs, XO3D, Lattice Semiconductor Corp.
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|   Model lvc330f040caaaaaaaou
[Model] lvc330f040caaaaaaaou
Model_type Output
Polarity   Non-Inverting
Enable   Active-High
Vmeas =  1.650V
Cref =  0.0F
Rref =  1.000M
Vref =  0.0V
C_comp   4.200pF   3.800pF   7.500pF
[Temperature Range]   25.000   0.105k   -40.000
[Voltage Range]   3.300V   3.140V   3.470V
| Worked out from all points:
|   slope of the pulldown table from 0 to 0.495 V, typ, clamps not added: 48.2 ohm
|   slope of the pullup table from 0 to 0.495 V, typ, clamps not added: 53.4 ohm
|   rising waveform, R_fixture 50.000, V_fixture 0.0: 20-80 % time 343ps typ, 382ps min, 271ps max; typ from 0 V to 1.17 V
|   rising waveform, R_fixture 50.000, V_fixture 3.300: 20-80 % time 199ps typ, 272ps min, 136ps max; typ from 2.15 V to 3.3 V
|   falling waveform, R_fixture 50.000, V_fixture 3.300: 20-80 % time 346ps typ, 363ps min, 325ps max; typ from 3.3 V to 2.15 V
|   falling waveform, R_fixture 50.000, V_fixture 0.0: 20-80 % time 183ps typ, 245ps min, 136ps max; typ from 1.17 V to 0 V
[Pulldown]
|Voltage   I(typ)   I(min)   I(max)
-3.3V     -4.507A    -3.482A    -6.263A
-1.1V     -420mA     -435.9mA   -408.3mA
-1V       -263.3mA   -314.6mA   -207.1mA
-900mV    -132.7mA   -203.2mA   -100.5mA
-800mV    -58.26mA   -109.1mA   -77.3mA
-700mV    -36.8mA    -43.35mA   -56.34mA
-600mV    -23.75mA   -16.43mA   -36.57mA
-500mV    -14.34mA   -9.251mA   -21.48mA
1.1V      18.59mA    12.67mA    27.38mA
4V        29.29mA    25.04mA    36.66mA
5.3V      77.93mA    61.17mA    110.8mA
6.6V      141.2mA    104.2mA    212.4mA
[Pullup]
|Voltage   I(typ)   I(min)   I(max)
-3.3V     135.9mA    102.8mA    211.9mA
-400mV    9.042mA    6.964mA    13.8mA
1.4V      -19.96mA   -14.57mA   -31.78mA
3.7V      -25.83mA   -21.92mA   -42.32mA
3.9V      -36.71mA   -89.3mA    -43.93mA
4.1V      -69.38mA   -284.1mA   -66.59mA
4.2V      -146.7mA   -403mA     -85.74mA
4.4V      -442.8mA   -658.2mA   -138.5mA
4.5V      -613.1mA   -790.6mA   -290.2mA
4.6V      -789.1mA   -924.9mA   -514mA
4.7V      -968.5mA   -1.061A    -759.2mA
6.6V      -4.534A    -3.729A    -5.846A
[Ramp]
| variable   typ   min   max
dV/dt_r   0.703/0.346n   0.506/0.375n   1.059/0.271n
dV/dt_f   0.687/0.344n   0.481/0.362n   0.969/0.323n
R_load = 50.000
[Rising Waveform]
R_fixture= 50.000
V_fixture= 0.0
V_fixture_min= 0.0
V_fixture_max= 0.0
|time   V(typ)   V(min)   V(max)
0s        27.06nV    64.78nV    334.4nV
562ps     44.9uV     26.52uV    -14.8mV
748ps     157.9uV    -3.973uV   1.042V
935ps     -23.82mV   96.93uV    1.463V
1.247ns   794.9mV    -2.284mV   1.664V
1.522ns   1.018V     164.9uV    1.72V
1.646ns   1.062V     238.2mV    1.735V
2.053ns   1.131V     703mV      1.756V
2.968ns   1.166V     824.5mV    1.764V
20ns      1.171V     842.7mV    1.765V
[Rising Waveform]
R_fixture= 50.000
V_fixture= 3.300
V_fixture_min= 3.140
V_fixture_max= 3.470
|time   V(typ)   V(min)   V(max)
0s        2.153V     2.336V     1.85V
502ps     2.153V     2.337V     1.865V
547ps     2.153V     2.337V     2.056V
666ps     2.154V     2.337V     3.026V
821ps     2.159V     2.336V     3.333V
1.054ns   2.973V     2.338V     3.414V
1.241ns   3.197V     2.327V     3.438V
1.678ns   3.272V     3V         3.458V
2.172ns   3.289V     3.115V     3.463V
20ns      3.297V     3.139V     3.465V
[Falling Waveform]
R_fixture= 50.000
V_fixture= 3.300
V_fixture_min= 3.140
V_fixture_max= 3.470
|time   V(typ)   V(min)   V(max)
0s        3.297V     3.139V     3.465V
563ps     3.297V     3.139V     3.493V
751ps     3.297V     3.139V     2.559V
953ps     3.331V     3.139V     2.176V
1.284ns   2.489V     3.139V     1.967V
1.61ns    2.277V     3.165V     1.897V
1.742ns   2.241V     2.923V     1.882V
2.179ns   2.184V     2.457V     1.86V
3.08ns    2.157V     2.353V     1.851V
20ns      2.153V     2.336V     1.85V
[Falling Waveform]
R_fixture= 50.000
V_fixture= 0.0
V_fixture_min= 0.0
V_fixture_max= 0.0
|time   V(typ)   V(min)   V(max)
0s        1.171V     842.7mV    1.765V
529ps     1.171V     842.7mV    1.744V
686ps     1.171V     842.7mV    463.3mV
880ps     1.163V     842.7mV    106.4mV
1.077ns   388.5mV    842.7mV    43.77mV
1.221ns   139.4mV    842.4mV    24.14mV
1.494ns   39.4mV     814mV      8.728mV
1.898ns   10.63mV    104.6mV    2.07mV
2.554ns   1.727mV    11.13mV    271.3uV
20ns      -97.54nV   112.2nV    302.2nV
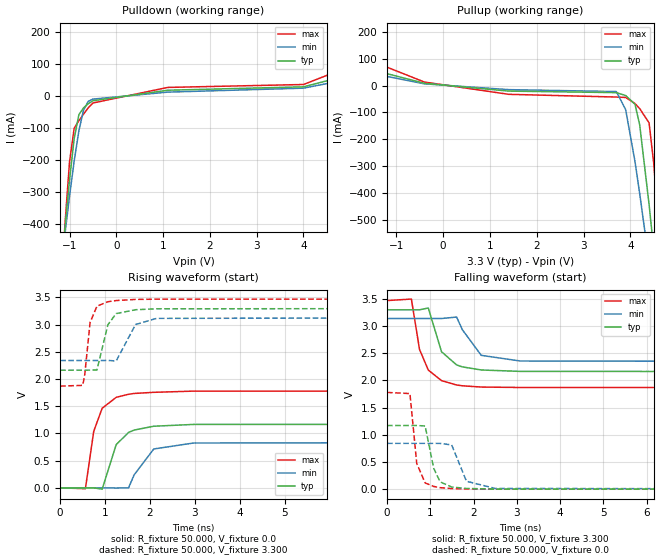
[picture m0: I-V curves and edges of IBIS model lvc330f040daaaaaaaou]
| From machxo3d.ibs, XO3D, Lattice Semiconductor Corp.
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|   Model lvc330f040daaaaaaaou
[Model] lvc330f040daaaaaaaou
Model_type Output
Polarity   Non-Inverting
Enable   Active-High
Vmeas =  1.650V
Cref =  0.0F
Rref =  1.000M
Vref =  0.0V
C_comp   4.200pF   3.800pF   7.500pF
[Temperature Range]   25.000   0.105k   -40.000
[Voltage Range]   3.300V   3.140V   3.470V
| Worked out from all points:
|   slope of the pulldown table from 0 to 0.495 V, typ, clamps not added: 48.2 ohm
|   slope of the pullup table from 0 to 0.495 V, typ, clamps not added: 53.2 ohm
|   rising waveform, R_fixture 50.000, V_fixture 0.0: 20-80 % time 343ps typ, 377ps min, 278ps max; typ from 0 V to 1.17 V
|   rising waveform, R_fixture 50.000, V_fixture 3.300: 20-80 % time 199ps typ, 273ps min, 135ps max; typ from 2.16 V to 3.3 V
|   falling waveform, R_fixture 50.000, V_fixture 3.300: 20-80 % time 343ps typ, 364ps min, 324ps max; typ from 3.3 V to 2.16 V
|   falling waveform, R_fixture 50.000, V_fixture 0.0: 20-80 % time 181ps typ, 246ps min, 138ps max; typ from 1.17 V to 0 V
[Pulldown]
|Voltage   I(typ)   I(min)   I(max)
-3.3V     -4.507A    -3.482A    -6.263A
-1.1V     -420mA     -435.9mA   -408.3mA
-1V       -263.3mA   -314.6mA   -207.1mA
-900mV    -132.7mA   -203.2mA   -100.5mA
-800mV    -58.26mA   -109.1mA   -77.3mA
-700mV    -36.8mA    -43.35mA   -56.34mA
-600mV    -23.75mA   -16.43mA   -36.57mA
-500mV    -14.34mA   -9.251mA   -21.48mA
1.1V      18.59mA    12.67mA    27.38mA
4V        29.28mA    25.1mA     36.55mA
5.3V      78.51mA    62.37mA    111mA
6.6V      144mA      108.8mA    214.5mA
[Pullup]
|Voltage   I(typ)   I(min)   I(max)
-3.3V     138.8mA    106.8mA    214.6mA
-400mV    8.988mA    6.957mA    13.64mA
1.4V      -20.18mA   -14.68mA   -32.2mA
3.7V      -25.83mA   -21.92mA   -42.32mA
3.9V      -36.71mA   -89.3mA    -43.93mA
4.1V      -69.38mA   -284.1mA   -66.59mA
4.2V      -146.7mA   -403mA     -85.74mA
4.4V      -442.8mA   -658.2mA   -138.5mA
4.5V      -613.1mA   -790.6mA   -290.2mA
4.6V      -789.1mA   -924.9mA   -514mA
4.7V      -968.5mA   -1.061A    -759.2mA
6.6V      -4.534A    -3.729A    -5.846A
[Ramp]
| variable   typ   min   max
dV/dt_r   0.703/0.346n   0.506/0.375n   1.068/0.278n
dV/dt_f   0.682/0.343n   0.480/0.362n   0.960/0.323n
R_load = 50.000
[Rising Waveform]
R_fixture= 50.000
V_fixture= 0.0
V_fixture_min= 0.0
V_fixture_max= 0.0
|time   V(typ)   V(min)   V(max)
0s        27.06nV    64.78nV    334.4nV
562ps     44.9uV     26.48uV    -14.8mV
748ps     157.9uV    -4.006uV   1.042V
935ps     -23.82mV   96.94uV    1.463V
1.247ns   794.9mV    -2.284mV   1.664V
1.522ns   1.018V     165uV      1.72V
1.646ns   1.062V     238.2mV    1.735V
2.083ns   1.133V     714.7mV    1.756V
2.968ns   1.166V     824.5mV    1.778V
20ns      1.171V     842.7mV    1.78V
[Rising Waveform]
R_fixture= 50.000
V_fixture= 3.300
V_fixture_min= 3.140
V_fixture_max= 3.470
|time   V(typ)   V(min)   V(max)
0s        2.163V     2.341V     1.87V
502ps     2.163V     2.341V     1.884V
547ps     2.163V     2.341V     2.077V
666ps     2.164V     2.341V     3.039V
819ps     2.167V     2.341V     3.339V
1.062ns   2.998V     2.342V     3.421V
1.246ns   3.203V     2.332V     3.443V
1.678ns   3.274V     3.002V     3.463V
2.145ns   3.291V     3.115V     3.468V
20ns      3.3V       3.14V      3.47V
[Falling Waveform]
R_fixture= 50.000
V_fixture= 3.300
V_fixture_min= 3.140
V_fixture_max= 3.470
|time   V(typ)   V(min)   V(max)
0s        3.3V       3.14V      3.47V
563ps     3.3V       3.14V      3.498V
751ps     3.3V       3.14V      2.571V
954ps     3.334V     3.14V      2.191V
1.259ns   2.529V     3.14V      1.997V
1.608ns   2.286V     3.167V     1.917V
1.741ns   2.25V      2.934V     1.902V
2.178ns   2.193V     2.462V     1.879V
3.082ns   2.167V     2.358V     1.871V
20ns      2.163V     2.341V     1.87V
[Falling Waveform]
R_fixture= 50.000
V_fixture= 0.0
V_fixture_min= 0.0
V_fixture_max= 0.0
|time   V(typ)   V(min)   V(max)
0s        1.171V     842.7mV    1.78V
529ps     1.171V     842.7mV    1.759V
687ps     1.171V     842.7mV    472.8mV
881ps     1.163V     842.7mV    114.3mV
1.078ns   385.3mV    842.7mV    50.01mV
1.227ns   134.4mV    842.4mV    27.42mV
1.494ns   39.4mV     814mV      10.66mV
1.836ns   12.78mV    145.5mV    3.043mV
2.504ns   2.021mV    12.52mV    352.9uV
20ns      -97.54nV   112.2nV    320.3nV
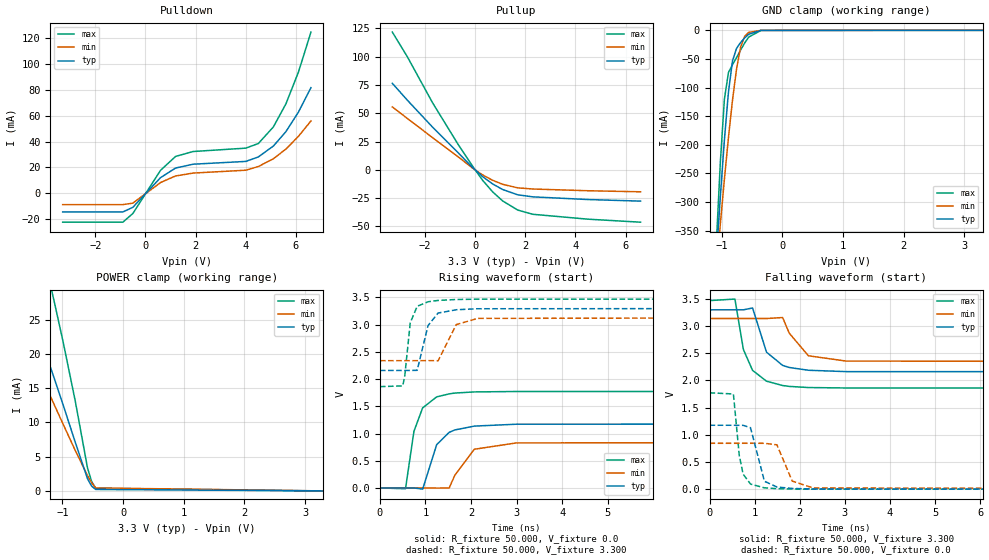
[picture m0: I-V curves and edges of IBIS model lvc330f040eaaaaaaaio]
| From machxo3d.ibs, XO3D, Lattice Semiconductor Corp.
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|   Model lvc330f040eaaaaaaaio
[Model] lvc330f040eaaaaaaaio
Model_type I/O
Polarity   Non-Inverting
Enable   Active-Low
Vinl =  0.800V
Vinh =  2.000V
Vmeas =  1.650V
Cref =  0.0F
Rref =  1.000M
Vref =  0.0V
C_comp   4.200pF   3.800pF   7.500pF
[Temperature Range]   25.000   0.105k   -40.000
[Voltage Range]   3.300V   3.140V   3.470V
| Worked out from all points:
|   slope of the pulldown table from 0 to 0.495 V, typ, clamps not added: 48.6 ohm
|   slope of the pullup table from 0 to 0.495 V, typ, clamps not added: 53.4 ohm
|   GND clamp passes 1 mA (typ) near -0.43 V on its own axis
|   POWER clamp passes 1 mA (typ) near -0.54 V on its own axis
|   rising waveform, R_fixture 50.000, V_fixture 0.0: 20-80 % time 344ps typ, 378ps min, 271ps max; typ from 0 V to 1.18 V
|   rising waveform, R_fixture 50.000, V_fixture 3.300: 20-80 % time 198ps typ, 272ps min, 135ps max; typ from 2.16 V to 3.3 V
|   falling waveform, R_fixture 50.000, V_fixture 3.300: 20-80 % time 345ps typ, 358ps min, 326ps max; typ from 3.3 V to 2.16 V
|   falling waveform, R_fixture 50.000, V_fixture 0.0: 20-80 % time 184ps typ, 246ps min, 137ps max; typ from 1.18 V to 0 V
[Pulldown]
|Voltage   I(typ)   I(min)   I(max)
-3.3V     -14.66mA   -8.951mA   -22.6mA
-900mV    -14.66mA   -8.951mA   -22.6mA
-500mV    -11.02mA   -7.807mA   -15.8mA
600mV     11.95mA    8.157mA    17.61mA
1.2V      19.4mA     13.27mA    28.41mA
1.9V      22.39mA    15.51mA    32.23mA
4V        24.55mA    17.73mA    34.86mA
4.5V      28.02mA    20.58mA    38.42mA
5.1V      36.46mA    26.61mA    51.29mA
5.6V      47.62mA    34.1mA     69.18mA
6.1V      62.81mA    44mA       93.83mA
6.6V      81.81mA    55.97mA    124.9mA
[Pullup]
|Voltage   I(typ)   I(min)   I(max)
-3.3V     76.54mA    55.7mA     121.8mA
-2.7V     61.58mA    45.45mA    99.96mA
-1.7V     37.91mA    28.6mA     59.51mA
-700mV    15.71mA    11.98mA    23.38mA
-100mV    2.145mA    1.619mA    3.301mA
300mV     -5.911mA   -4.416mA   -9.19mA
700mV     -12.39mA   -9.179mA   -19.41mA
1.1V      -17.33mA   -12.72mA   -27.42mA
1.7V      -22.01mA   -15.86mA   -35.48mA
2.3V      -23.82mA   -16.89mA   -39.22mA
4.5V      -26.18mA   -18.42mA   -43.54mA
6.6V      -27.59mA   -19.35mA   -46.21mA
[GND_clamp]
|Voltage   I(typ)   I(min)   I(max)
-3.3V     -4.507A    -3.482A    -6.263A
-1.089V   -398.4mA   -420.6mA   -374.7mA
-1.022V   -290.7mA   -338.6mA   -230.6mA
-955mV    -191.3mA   -260.2mA   -120mA
-888mV    -107.5mA   -187mA     -73.64mA
-821mV    -52.96mA   -121.4mA   -59.79mA
-754mV    -31.36mA   -66.92mA   -47.4mA
-687mV    -21.12mA   -28.79mA   -34.18mA
-620mV    -13.16mA   -10.19mA   -21.93mA
-553mV    -6.814mA   -3.53mA    -11.64mA
-352mV    -96.36uA   -46.21uA   -149.8uA
3.3V      0A         0A         0A
[POWER_clamp]
|Voltage   I(typ)   I(min)   I(max)
-3.3V     59.07mA    46.89mA    89.53mA
-1.993V   37.2mA     28.86mA    58.21mA
-1.926V   35.72mA    27.66mA    56.06mA
-1.591V   27.93mA    21.43mA    44.68mA
-1.189V   17.86mA    13.66mA    29.77mA
-1.122V   16.11mA    12.35mA    27.14mA
-988mV    12.56mA    9.745mA    21.76mA
-787mV    7.078mA    5.887mA    13.07mA
-586mV    1.773mA    2.247mA    3.338mA
-519mV    707uA      1.205mA    1.383mA
-452mV    214.8uA    435.5uA    392.3uA
3.3V      0A         0A         0A
[Ramp]
| variable   typ   min   max
dV/dt_r   0.705/0.347n   0.507/0.376n   1.064/0.271n
dV/dt_f   0.685/0.344n   0.481/0.362n   0.965/0.324n
R_load = 50.000
[Rising Waveform]
R_fixture= 50.000
V_fixture= 0.0
V_fixture_min= 0.0
V_fixture_max= 0.0
|time   V(typ)   V(min)   V(max)
0s        27.69nV    65.53nV    348nV
562ps     50.05uV    29.69uV    -14.85mV
747ps     200.3uV    -1.37uV    1.041V
938ps     -22.47mV   119.6uV    1.471V
1.246ns   795.2mV    -2.287mV   1.673V
1.52ns    1.021V     -1.648mV   1.728V
1.642ns   1.065V     229mV      1.743V
2.07ns    1.136V     710.9mV    1.764V
2.997ns   1.171V     827.2mV    1.772V
20ns      1.176V     844.4mV    1.773V
[Rising Waveform]
R_fixture= 50.000
V_fixture= 3.300
V_fixture_min= 3.140
V_fixture_max= 3.470
|time   V(typ)   V(min)   V(max)
0s        2.158V     2.338V     1.861V
502ps     2.158V     2.338V     1.875V
547ps     2.158V     2.338V     2.068V
666ps     2.159V     2.338V     3.034V
818ps     2.161V     2.338V     3.337V
1.056ns   2.982V     2.34V      3.42V
1.277ns   3.213V     2.337V     3.445V
1.678ns   3.274V     3.002V     3.462V
2.147ns   3.292V     3.115V     3.468V
20ns      3.3V       3.14V      3.47V
[Falling Waveform]
R_fixture= 50.000
V_fixture= 3.300
V_fixture_min= 3.140
V_fixture_max= 3.470
|time   V(typ)   V(min)   V(max)
0s        3.3V       3.14V      3.47V
563ps     3.3V       3.14V      3.498V
751ps     3.3V       3.14V      2.569V
954ps     3.334V     3.14V      2.186V
1.263ns   2.521V     3.14V      1.987V
1.621ns   2.277V     3.158V     1.907V
1.767ns   2.239V     2.87V      1.891V
2.191ns   2.188V     2.455V     1.87V
3.027ns   2.163V     2.357V     1.862V
20ns      2.158V     2.338V     1.861V
[Falling Waveform]
R_fixture= 50.000
V_fixture= 0.0
V_fixture_min= 0.0
V_fixture_max= 0.0
|time   V(typ)   V(min)   V(max)
0s        1.176V     844.4mV    1.773V
529ps     1.176V     844.3mV    1.752V
659ps     1.175V     844.3mV    621.5mV
744ps     1.175V     844.5mV    276.7mV
909ps     1.13V      844.5mV    93.36mV
1.217ns   145.1mV    844mV      24.8mV
1.494ns   40.13mV    815.7mV    9.129mV
1.833ns   13.04mV    149mV      2.906mV
2.297ns   3.556mV    22.31mV    575.2uV
20ns      -94.92nV   130.1nV    139.1nV
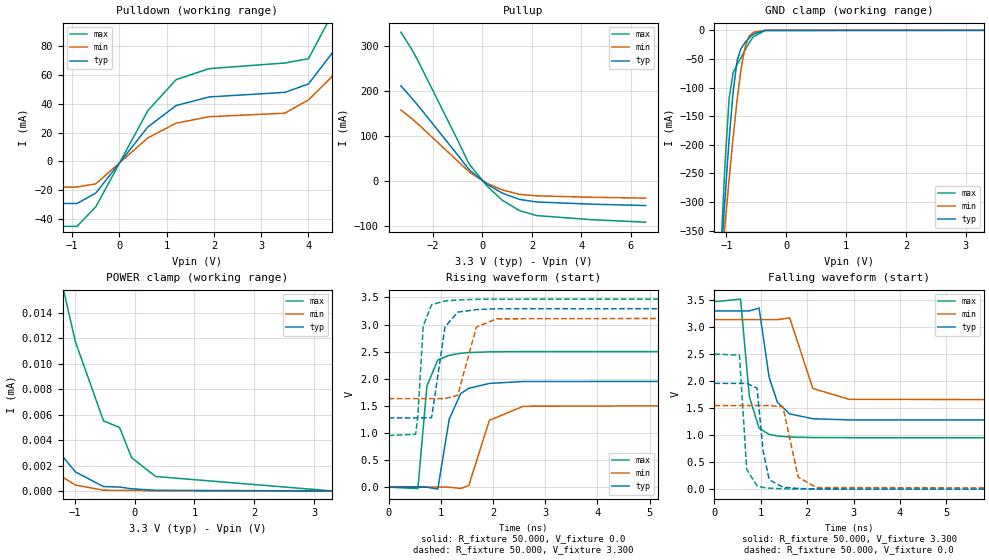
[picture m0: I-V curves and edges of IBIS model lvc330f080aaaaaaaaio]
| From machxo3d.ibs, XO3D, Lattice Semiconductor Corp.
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|   Model lvc330f080aaaaaaaaio
[Model] lvc330f080aaaaaaaaio
Model_type I/O
Polarity   Non-Inverting
Enable   Active-Low
Vinl =  0.800V
Vinh =  2.000V
Vmeas =  1.650V
Cref =  0.0F
Rref =  1.000M
Vref =  0.0V
C_comp   4.200pF   3.800pF   7.500pF
[Temperature Range]   25.000   0.105k   -40.000
[Voltage Range]   3.300V   3.140V   3.470V
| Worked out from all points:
|   slope of the pulldown table from 0 to 0.495 V, typ, clamps not added: 24.3 ohm
|   slope of the pullup table from 0 to 0.495 V, typ, clamps not added: 26.7 ohm
|   GND clamp passes 1 mA (typ) near -0.43 V on its own axis
|   rising waveform, R_fixture 50.000, V_fixture 0.0: 20-80 % time 241ps typ, 325ps min, 147ps max; typ from 0 V to 1.96 V
|   rising waveform, R_fixture 50.000, V_fixture 3.300: 20-80 % time 155ps typ, 231ps min, 93.1ps max; typ from 1.28 V to 3.3 V
|   falling waveform, R_fixture 50.000, V_fixture 3.300: 20-80 % time 265ps typ, 333ps min, 186ps max; typ from 3.3 V to 1.28 V
|   falling waveform, R_fixture 50.000, V_fixture 0.0: 20-80 % time 135ps typ, 200ps min, 93.5ps max; typ from 1.96 V to 0 V
[Pulldown]
|Voltage   I(typ)   I(min)   I(max)
-3.3V     -29.32mA   -17.9mA    -45.21mA
-900mV    -29.32mA   -17.9mA    -45.21mA
-500mV    -22.04mA   -15.61mA   -31.59mA
600mV     23.9mA     16.31mA    35.23mA
1.2V      38.8mA     26.54mA    56.81mA
1.9V      44.78mA    31.02mA    64.46mA
3.5V      47.95mA    33.48mA    68.37mA
4V        53.77mA    42.73mA    71.35mA
4.7V      83.76mA    65.34mA    114.8mA
5.3V      118.2mA    90.43mA    168.1mA
5.9V      161.7mA    120.6mA    237.3mA
6.6V      222.2mA    159.7mA    335.8mA
[Pullup]
|Voltage   I(typ)   I(min)   I(max)
-3.3V     212.1mA    158.1mA    332mA
-2.9V     187.2mA    140.6mA    297.1mA
-2.6V     167.7mA    126.4mA    267.4mA
-1V       57.59mA    43.96mA    90.54mA
-600mV    29.02mA    23.04mA    44.14mA
-500mV    22.91mA    18.07mA    34.77mA
200mV     -8.086mA   -6.051mA   -12.55mA
800mV     -27.53mA   -20.35mA   -43.24mA
1.5V      -41.6mA    -30.18mA   -66.6mA
2.2V      -47.32mA   -33.59mA   -77.7mA
4.4V      -52.17mA   -36.73mA   -86.76mA
6.6V      -55.19mA   -38.7mA    -92.41mA
[GND_clamp]
|Voltage   I(typ)   I(min)   I(max)
-3.3V     -4.507A    -3.482A    -6.263A
-1.089V   -398.4mA   -420.6mA   -374.7mA
-1.022V   -290.7mA   -338.6mA   -230.6mA
-955mV    -191.3mA   -260.2mA   -120mA
-888mV    -107.5mA   -187mA     -73.64mA
-821mV    -52.96mA   -121.4mA   -59.79mA
-754mV    -31.36mA   -66.92mA   -47.4mA
-687mV    -21.12mA   -28.79mA   -34.18mA
-620mV    -13.16mA   -10.19mA   -21.93mA
-553mV    -6.814mA   -3.53mA    -11.64mA
-352mV    -96.36uA   -46.21uA   -149.8uA
3.3V      0A         0A         0A
[POWER_clamp]
|Voltage   I(typ)   I(min)   I(max)
-3.3V     732.2uA    455.9uA    1.265mA
-2.663V   69.44uA    15.46uA    306.8uA
-2.529V   27.69uA    10.95uA    164.1uA
-2.328V   15.69uA    8.497uA    64.68uA
-1.725V   7.348uA    3.693uA    30.69uA
-1.189V   2.632uA    1.04uA     15.85uA
-988mV    1.494uA    463nA      11.72uA
-519mV    342.8nA    54.75nA    5.51uA
-251mV    305.1nA    47.62nA    4.994uA
-50mV     169nA      47.62nA    2.616uA
352mV     50.67nA    4.149nA    1.135uA
3.3V      0A         0A         0A
[Ramp]
| variable   typ   min   max
dV/dt_r   1.175/0.242n   0.929/0.325n   1.501/0.146n
dV/dt_f   1.213/0.269n   0.904/0.330n   1.510/0.188n
R_load = 50.000
[Rising Waveform]
R_fixture= 50.000
V_fixture= 0.0
V_fixture_min= 0.0
V_fixture_max= 0.0
|time   V(typ)   V(min)   V(max)
0s        17.95nV    45.29nV    212.7nV
561ps     41.13uV    -2.929uV   -26.47mV
734ps     156.1uV    -2.929uV   1.866V
942ps     -36.85mV   21uV       2.346V
1.161ns   1.253V     262.2uV    2.433V
1.381ns   1.727V     -24.13mV   2.47V
1.536ns   1.824V     31.19mV    2.482V
1.931ns   1.914V     1.234V     2.496V
2.58ns    1.949V     1.492V     2.501V
20ns      1.959V     1.548V     2.502V
[Rising Waveform]
R_fixture= 50.000
V_fixture= 3.300
V_fixture_min= 3.140
V_fixture_max= 3.470
|time   V(typ)   V(min)   V(max)
0s        1.278V     1.633V     953.3mV
517ps     1.278V     1.633V     976.5mV
559ps     1.278V     1.633V     1.298V
663ps     1.279V     1.633V     2.971V
824ps     1.282V     1.633V     3.367V
1.081ns   2.956V     1.635V     3.434V
1.324ns   3.229V     1.693V     3.453V
1.681ns   3.275V     2.952V     3.465V
2.066ns   3.291V     3.106V     3.468V
20ns      3.3V       3.14V      3.47V
[Falling Waveform]
R_fixture= 50.000
V_fixture= 3.300
V_fixture_min= 3.140
V_fixture_max= 3.470
|time   V(typ)   V(min)   V(max)
0s        3.3V       3.14V      3.47V
563ps     3.3V       3.14V      3.52V
753ps     3.3V       3.14V      1.716V
963ps     3.354V     3.14V      1.128V
1.178ns   2.077V     3.139V     1.015V
1.358ns   1.608V     3.138V     984.9mV
1.622ns   1.394V     3.171V     965.7mV
2.122ns   1.304V     1.865V     955.5mV
2.904ns   1.282V     1.664V     953.4mV
20ns      1.278V     1.633V     953.2mV
[Falling Waveform]
R_fixture= 50.000
V_fixture= 0.0
V_fixture_min= 0.0
V_fixture_max= 0.0
|time   V(typ)   V(min)   V(max)
0s        1.959V     1.548V     2.502V
539ps     1.959V     1.548V     2.481V
696ps     1.959V     1.548V     364.6mV
919ps     1.871V     1.548V     59.86mV
1.047ns   722mV      1.548V     33.73mV
1.181ns   174.7mV    1.548V     19.4mV
1.476ns   37.08mV    1.527V     6.504mV
1.805ns   12.83mV    222.7mV    1.833mV
2.203ns   3.867mV    29.43mV    527.7uV
20ns      -7.76nV    -5.929nV   226.5nV
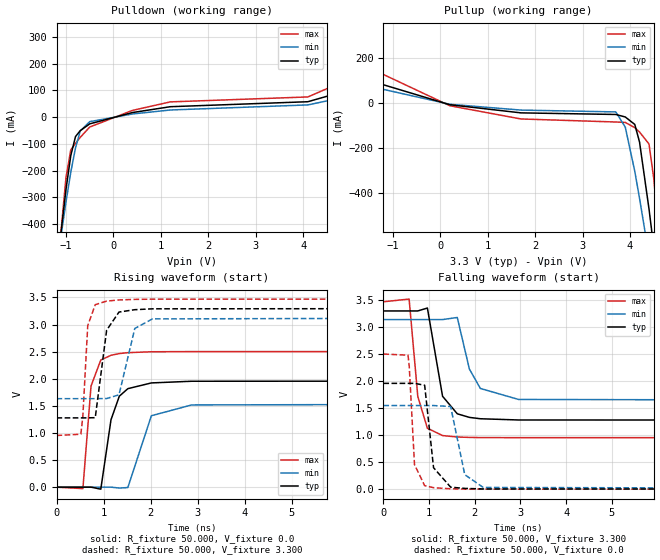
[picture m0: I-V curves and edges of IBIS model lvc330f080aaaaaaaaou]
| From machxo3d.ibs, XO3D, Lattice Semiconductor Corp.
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|   Model lvc330f080aaaaaaaaou
[Model] lvc330f080aaaaaaaaou
Model_type Output
Polarity   Non-Inverting
Enable   Active-High
Vmeas =  1.650V
Cref =  0.0F
Rref =  1.000M
Vref =  0.0V
C_comp   4.200pF   3.800pF   7.500pF
[Temperature Range]   25.000   0.105k   -40.000
[Voltage Range]   3.300V   3.140V   3.470V
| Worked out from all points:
|   slope of the pulldown table from 0 to 0.495 V, typ, clamps not added: 24.3 ohm
|   slope of the pullup table from 0 to 0.495 V, typ, clamps not added: 26.7 ohm
|   rising waveform, R_fixture 50.000, V_fixture 0.0: 20-80 % time 242ps typ, 328ps min, 147ps max; typ from 0 V to 1.96 V
|   rising waveform, R_fixture 50.000, V_fixture 3.300: 20-80 % time 154ps typ, 230ps min, 93.2ps max; typ from 1.28 V to 3.3 V
|   falling waveform, R_fixture 50.000, V_fixture 3.300: 20-80 % time 266ps typ, 332ps min, 186ps max; typ from 3.3 V to 1.28 V
|   falling waveform, R_fixture 50.000, V_fixture 0.0: 20-80 % time 134ps typ, 199ps min, 93.5ps max; typ from 1.96 V to 0 V
[Pulldown]
|Voltage   I(typ)   I(min)   I(max)
-3.3V     -4.507A    -3.482A    -6.263A
-1.1V     -423.3mA   -437.5mA   -416.6mA
-1V       -269.7mA   -316.9mA   -225.1mA
-900mV    -144.4mA   -206.8mA   -123.1mA
-800mV    -72.88mA   -115.2mA   -98.37mA
-700mV    -50.68mA   -52.02mA   -75.84mA
-500mV    -25.29mA   -17.01mA   -37.18mA
400mV     16.94mA    11.56mA    24.96mA
1.2V      38.8mA     26.54mA    56.81mA
4.1V      57.44mA    45.51mA    75.3mA
5.3V      118.2mA    90.43mA    168.1mA
6.6V      222.9mA    160.3mA    336.8mA
[Pullup]
|Voltage   I(typ)   I(min)   I(max)
-3.3V     212.9mA    158.6mA    333.3mA
200mV     -8.086mA   -6.051mA   -12.55mA
1.7V      -44.02mA   -31.73mA   -70.96mA
3.7V      -51.13mA   -39.8mA    -84.42mA
3.9V      -62.23mA   -107.3mA   -86.34mA
4.1V      -95.12mA   -302.3mA   -109.4mA
4.2V      -172.6mA   -421.2mA   -128.7mA
4.4V      -468.8mA   -676.6mA   -181.8mA
4.5V      -639.3mA   -809mA     -333.7mA
4.6V      -815.4mA   -943.4mA   -557.7mA
4.7V      -994.9mA   -1.079A    -803mA
6.6V      -4.562A    -3.748A    -5.893A
[Ramp]
| variable   typ   min   max
dV/dt_r   1.175/0.242n   0.929/0.325n   1.501/0.146n
dV/dt_f   1.213/0.269n   0.904/0.330n   1.510/0.188n
R_load = 50.000
[Rising Waveform]
R_fixture= 50.000
V_fixture= 0.0
V_fixture_min= 0.0
V_fixture_max= 0.0
|time   V(typ)   V(min)   V(max)
0s        17.95nV    45.29nV    212.7nV
561ps     39.08uV    -4.755uV   -26.47mV
734ps     155.5uV    -4.755uV   1.866V
942ps     -36.84mV   103uV      2.346V
1.159ns   1.244V     262.2uV    2.433V
1.336ns   1.678V     -16.44mV   2.465V
1.517ns   1.817V     -6.959mV   2.481V
2.018ns   1.923V     1.318V     2.498V
2.876ns   1.954V     1.517V     2.501V
20ns      1.959V     1.548V     2.502V
[Rising Waveform]
R_fixture= 50.000
V_fixture= 3.300
V_fixture_min= 3.140
V_fixture_max= 3.470
|time   V(typ)   V(min)   V(max)
0s        1.278V     1.633V     953.3mV
517ps     1.278V     1.633V     976.5mV
559ps     1.278V     1.633V     1.298V
664ps     1.279V     1.633V     2.979V
824ps     1.282V     1.633V     3.367V
1.066ns   2.895V     1.635V     3.432V
1.329ns   3.23V      1.704V     3.454V
1.665ns   3.274V     2.927V     3.464V
2.041ns   3.29V      3.104V     3.468V
20ns      3.3V       3.14V      3.47V
[Falling Waveform]
R_fixture= 50.000
V_fixture= 3.300
V_fixture_min= 3.140
V_fixture_max= 3.470
|time   V(typ)   V(min)   V(max)
0s        3.3V       3.14V      3.47V
563ps     3.3V       3.14V      3.52V
753ps     3.3V       3.14V      1.716V
963ps     3.354V     3.14V      1.128V
1.295ns   1.72V      3.14V      992.4mV
1.617ns   1.396V     3.179V     966.1mV
1.882ns   1.329V     2.225V     958.3mV
2.122ns   1.304V     1.865V     955.4mV
2.959ns   1.281V     1.661V     953.4mV
20ns      1.278V     1.633V     953.2mV
[Falling Waveform]
R_fixture= 50.000
V_fixture= 0.0
V_fixture_min= 0.0
V_fixture_max= 0.0
|time   V(typ)   V(min)   V(max)
0s        1.959V     1.548V     2.502V
539ps     1.959V     1.548V     2.481V
566ps     1.959V     1.548V     2.27V
681ps     1.959V     1.548V     454.4mV
903ps     1.924V     1.548V     65.09mV
1.098ns   397.1mV    1.548V     27.44mV
1.472ns   37.05mV    1.531V     6.686mV
1.781ns   14.17mV    268.6mV    1.937mV
2.186ns   4.072mV    31.52mV    577.4uV
20ns      52.14nV    183.3nV    116.3nV
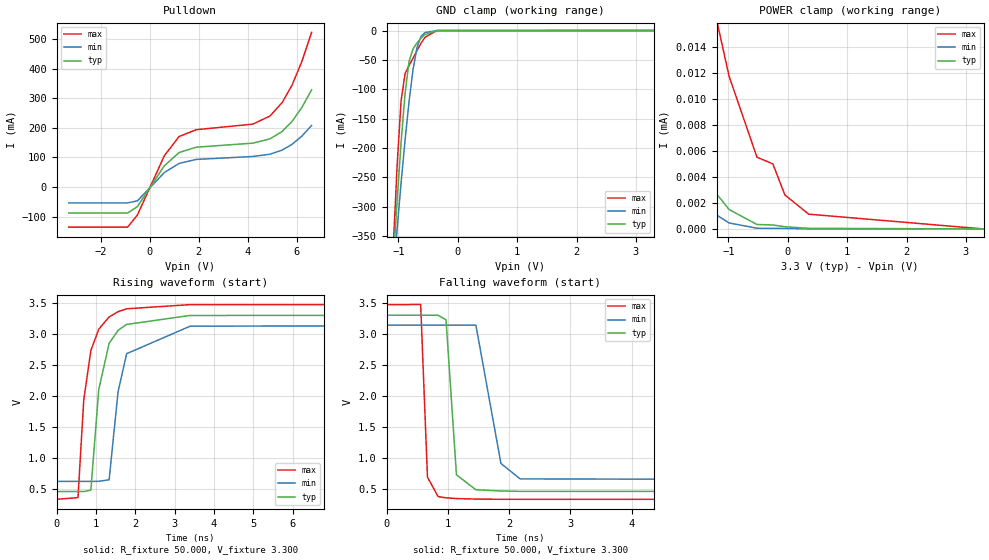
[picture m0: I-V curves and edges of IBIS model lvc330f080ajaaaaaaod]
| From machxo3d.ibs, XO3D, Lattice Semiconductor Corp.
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|   Model lvc330f080ajaaaaaaod
[Model] lvc330f080ajaaaaaaod
Model_type I/O_open_drain
Polarity   Non-Inverting
Enable   Active-Low
Vinl =  0.800V
Vinh =  2.000V
Vmeas =  1.650V
Cref =  0.0F
Rref = 10.00k
Vref = 3.30V
C_comp   4.200pF   3.800pF   7.500pF
[Temperature Range]   25.000   0.105k   -40.000
[Voltage Range]   3.300V   3.140V   3.470V
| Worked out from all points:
|   slope of the pulldown table from 0 to 0.495 V, typ, clamps not added: 8.1 ohm
|   GND clamp passes 1 mA (typ) near -0.43 V on its own axis
|   rising waveform, R_fixture 50.000, V_fixture 3.300: 20-80 % time 325ps typ, 325ps min, 326ps max; typ from 0.453 V to 3.3 V
|   falling waveform, R_fixture 50.000, V_fixture 3.300: 20-80 % time 94.6ps typ, 147ps min, 60.3ps max; typ from 3.3 V to 0.452 V
[Pulldown]
|Voltage   I(typ)   I(min)   I(max)
-3.3V     -87.95mA   -53.71mA   -135.6mA
-900mV    -87.95mA   -53.71mA   -135.6mA
-500mV    -66.12mA   -46.84mA   -94.78mA
600mV     71.71mA    48.94mA    105.7mA
1.2V      116.4mA    79.62mA    170.4mA
1.9V      134.4mA    93.06mA    193.4mA
4.2V      148mA      103mA      212.2mA
4.9V      162.3mA    110.6mA    239.3mA
5.4V      187.6mA    124.6mA    285mA
5.8V      221.1mA    143.8mA    343.4mA
6.2V      268mA      171.5mA    422.9mA
6.6V      327.9mA    207.8mA    522.2mA
[GND_clamp]
|Voltage   I(typ)   I(min)   I(max)
-3.3V     -4.507A    -3.482A    -6.263A
-1.089V   -398.4mA   -420.6mA   -374.7mA
-1.022V   -290.7mA   -338.6mA   -230.6mA
-955mV    -191.3mA   -260.2mA   -120mA
-888mV    -107.5mA   -187mA     -73.64mA
-821mV    -52.96mA   -121.4mA   -59.79mA
-754mV    -31.36mA   -66.92mA   -47.4mA
-687mV    -21.12mA   -28.79mA   -34.18mA
-620mV    -13.16mA   -10.19mA   -21.93mA
-553mV    -6.814mA   -3.53mA    -11.64mA
-352mV    -96.36uA   -46.21uA   -149.8uA
3.3V      0A         0A         0A
[POWER_clamp]
|Voltage   I(typ)   I(min)   I(max)
-3.3V     732.2uA    455.9uA    1.265mA
-2.663V   69.44uA    15.46uA    306.8uA
-2.529V   27.69uA    10.95uA    164.1uA
-2.328V   15.69uA    8.497uA    64.68uA
-1.725V   7.348uA    3.693uA    30.69uA
-1.189V   2.632uA    1.04uA     15.85uA
-988mV    1.494uA    463nA      11.72uA
-519mV    342.8nA    54.73nA    5.51uA
-251mV    305.1nA    47.61nA    4.994uA
-50mV     169nA      47.61nA    2.616uA
352mV     50.67nA    4.149nA    1.135uA
3.3V      0A         0A         0A
[Ramp]
| variable   typ   min   max
dV/dt_r   1.708/0.324n   1.514/0.324n   1.886/0.326n
dV/dt_f   1.709/94.310p   1.514/0.147n   1.886/60.113p
R_load = 50.000
[Rising Waveform]
R_fixture= 50.000
V_fixture= 3.300
V_fixture_min= 3.140
V_fixture_max= 3.470
|time   V(typ)   V(min)   V(max)
0s        452.6mV    617mV      327.1mV
545ps     452.6mV    617mV      354.9mV
692ps     453.2mV    617mV      1.932V
872ps     476.3mV    617mV      2.727V
1.073ns   2.098V     617.7mV    3.072V
1.336ns   2.844V     642.1mV    3.269V
1.564ns   3.053V     2.066V     3.354V
1.782ns   3.149V     2.677V     3.401V
3.394ns   3.293V     3.12V      3.468V
20ns      3.3V       3.14V      3.47V
[Falling Waveform]
R_fixture= 50.000
V_fixture= 3.300
V_fixture_min= 3.140
V_fixture_max= 3.470
|time   V(typ)   V(min)   V(max)
0s        3.3V       3.14V      3.47V
557ps     3.3V       3.14V      3.473V
668ps     3.299V     3.14V      685.3mV
842ps     3.299V     3.14V      371.2mV
971ps     3.225V     3.14V      351.3mV
1.141ns   722.7mV    3.139V     339.2mV
1.458ns   481.6mV    3.139V     330.5mV
1.867ns   461.3mV    905.5mV    327.6mV
2.18ns    455.7mV    656.9mV    327.2mV
20ns      452.5mV    616.8mV    326.8mV
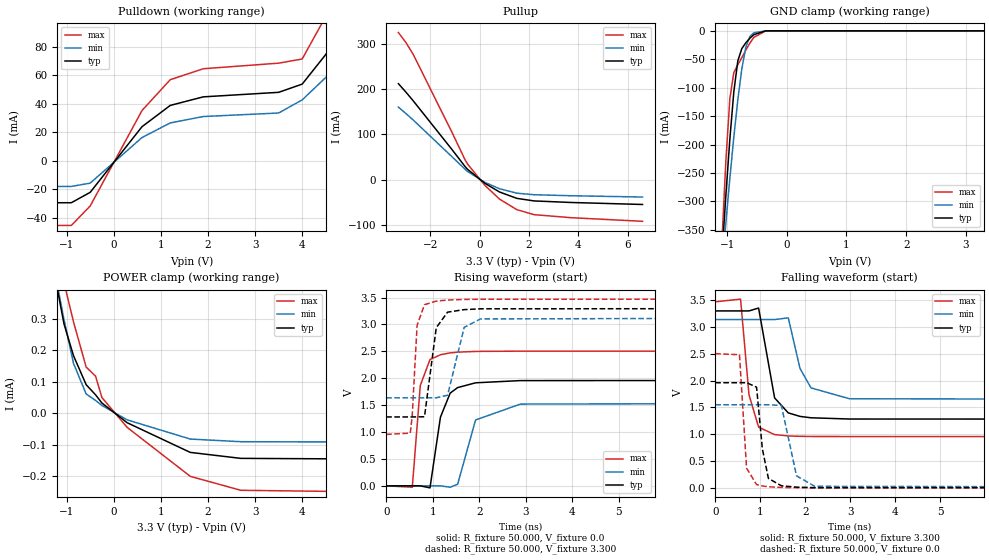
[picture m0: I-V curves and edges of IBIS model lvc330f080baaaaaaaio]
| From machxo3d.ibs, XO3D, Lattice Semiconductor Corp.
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|   Model lvc330f080baaaaaaaio
[Model] lvc330f080baaaaaaaio
Model_type I/O
Polarity   Non-Inverting
Enable   Active-Low
Vinl =  0.800V
Vinh =  2.000V
Vmeas =  1.650V
Cref =  0.0F
Rref =  1.000M
Vref =  0.0V
C_comp   4.200pF   3.800pF   7.500pF
[Temperature Range]   25.000   0.105k   -40.000
[Voltage Range]   3.300V   3.140V   3.470V
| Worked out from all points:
|   slope of the pulldown table from 0 to 0.495 V, typ, clamps not added: 24.3 ohm
|   slope of the pullup table from 0 to 0.495 V, typ, clamps not added: 26.7 ohm
|   GND clamp passes 1 mA (typ) near -0.43 V on its own axis
|   POWER clamp passes 1 mA (typ) near -1.85 V on its own axis
|   rising waveform, R_fixture 50.000, V_fixture 0.0: 20-80 % time 243ps typ, 326ps min, 146ps max; typ from 0.002 V to 1.96 V
|   rising waveform, R_fixture 50.000, V_fixture 3.300: 20-80 % time 155ps typ, 230ps min, 93.1ps max; typ from 1.28 V to 3.3 V
|   falling waveform, R_fixture 50.000, V_fixture 3.300: 20-80 % time 266ps typ, 328ps min, 187ps max; typ from 3.3 V to 1.28 V
|   falling waveform, R_fixture 50.000, V_fixture 0.0: 20-80 % time 135ps typ, 200ps min, 93.7ps max; typ from 1.96 V to 0.002 V
[Pulldown]
|Voltage   I(typ)   I(min)   I(max)
-3.3V     -29.32mA   -17.9mA    -45.21mA
-900mV    -29.32mA   -17.9mA    -45.21mA
-500mV    -22.04mA   -15.61mA   -31.59mA
600mV     23.9mA     16.31mA    35.23mA
1.2V      38.8mA     26.54mA    56.81mA
1.9V      44.78mA    31.02mA    64.46mA
3.5V      47.95mA    33.48mA    68.37mA
4V        53.7mA     42.66mA    71.29mA
4.6V      78.57mA    61.48mA    107.1mA
5.3V      117.8mA    90.48mA    167.4mA
5.9V      161.5mA    121.2mA    236.5mA
6.6V      222.1mA    162.3mA    332.3mA
[Pullup]
|Voltage   I(typ)   I(min)   I(max)
-3.3V     212.2mA    160.3mA    325.3mA
-3V       193.8mA    146.3mA    303.7mA
-2.7V     174.3mA    131.8mA    277mA
-1.1V     64.48mA    49.08mA    101.4mA
-600mV    28.97mA    23.03mA    44.05mA
-500mV    22.89mA    18.05mA    34.72mA
200mV     -8.086mA   -6.051mA   -12.55mA
800mV     -27.53mA   -20.35mA   -43.24mA
1.5V      -41.6mA    -30.18mA   -66.6mA
2.2V      -47.32mA   -33.59mA   -77.7mA
3.7V      -50.76mA   -35.84mA   -84.41mA
6.6V      -55.19mA   -38.7mA    -92.41mA
[GND_clamp]
|Voltage   I(typ)   I(min)   I(max)
-3.3V     -4.506A    -3.482A    -6.262A
-1.089V   -398.3mA   -420.5mA   -374.5mA
-1.022V   -290.6mA   -338.5mA   -230.4mA
-955mV    -191.2mA   -260.1mA   -119.8mA
-888mV    -107.4mA   -186.9mA   -73.47mA
-821mV    -52.87mA   -121.3mA   -59.62mA
-754mV    -31.28mA   -66.86mA   -47.24mA
-687mV    -21.04mA   -28.74mA   -34.02mA
-620mV    -13.09mA   -10.15mA   -21.79mA
-553mV    -6.755mA   -3.505mA   -11.52mA
-352mV    -90.18uA   -45.39uA   -119.9uA
3.3V      0A         0A         0A
[POWER_clamp]
|Voltage   I(typ)   I(min)   I(max)
-3.3V     3.967mA    2.512mA    11.53mA
-1.323V   507.3uA    506.4uA    605.6uA
-1.189V   387.7uA    399.8uA    501.1uA
-1.055V   282.8uA    296.7uA    413.8uA
-854mV    182.6uA    158.2uA    289.7uA
-586mV    90.73uA    61.33uA    146.6uA
-385mV    58.36uA    40.66uA    117.5uA
-251mV    32.53uA    24.74uA    49.87uA
285mV     -29.95uA   -20.85uA   -44.72uA
1.625V    -124uA     -81.72uA   -199.9uA
2.697V    -142.9uA   -90.03uA   -244.1uA
6.6V      -145.9uA   -91.75uA   -251.2uA
[Ramp]
| variable   typ   min   max
dV/dt_r   1.176/0.241n   0.930/0.324n   1.501/0.146n
dV/dt_f   1.211/0.270n   0.902/0.331n   1.507/0.188n
R_load = 50.000
[Rising Waveform]
R_fixture= 50.000
V_fixture= 0.0
V_fixture_min= 0.0
V_fixture_max= 0.0
|time   V(typ)   V(min)   V(max)
0s        2.128mV    1.725mV    2.736mV
561ps     2.17mV     1.721mV    -23.15mV
733ps     2.265mV    1.721mV    1.866V
941ps     -35.02mV   1.795mV    2.348V
1.166ns   1.278V     1.978mV    2.437V
1.375ns   1.725V     -22.48mV   2.472V
1.535ns   1.827V     31.78mV    2.485V
1.921ns   1.916V     1.226V     2.499V
2.886ns   1.957V     1.521V     2.504V
20ns      1.962V     1.551V     2.504V
[Rising Waveform]
R_fixture= 50.000
V_fixture= 3.300
V_fixture_min= 3.140
V_fixture_max= 3.470
|time   V(typ)   V(min)   V(max)
0s        1.282V     1.637V     957.6mV
517ps     1.282V     1.637V     981.4mV
558ps     1.282V     1.637V     1.291V
664ps     1.283V     1.637V     2.983V
823ps     1.285V     1.637V     3.367V
1.076ns   2.939V     1.638V     3.433V
1.319ns   3.228V     1.685V     3.453V
1.676ns   3.275V     2.945V     3.464V
2.024ns   3.29V      3.102V     3.468V
20ns      3.3V       3.14V      3.47V
[Falling Waveform]
R_fixture= 50.000
V_fixture= 3.300
V_fixture_min= 3.140
V_fixture_max= 3.470
|time   V(typ)   V(min)   V(max)
0s        3.3V       3.14V      3.47V
563ps     3.3V       3.14V      3.52V
750ps     3.3V       3.14V      1.737V
963ps     3.354V     3.14V      1.134V
1.318ns   1.679V     3.139V     994.5mV
1.622ns   1.399V     3.171V     970.2mV
1.882ns   1.334V     2.227V     962.3mV
2.126ns   1.308V     1.865V     959.9mV
2.98ns    1.285V     1.663V     957.7mV
20ns      1.282V     1.637V     957.5mV
[Falling Waveform]
R_fixture= 50.000
V_fixture= 0.0
V_fixture_min= 0.0
V_fixture_max= 0.0
|time   V(typ)   V(min)   V(max)
0s        1.962V     1.551V     2.504V
539ps     1.962V     1.551V     2.483V
696ps     1.962V     1.551V     369.2mV
918ps     1.879V     1.551V     63.11mV
1.047ns   726.5mV    1.551V     36.63mV
1.181ns   178mV      1.551V     22.29mV
1.469ns   40.41mV    1.537V     9.409mV
1.805ns   14.92mV    225.5mV    4.649mV
2.208ns   5.948mV    30.79mV    3.298mV
20ns      2.128mV    1.725mV    2.736mV
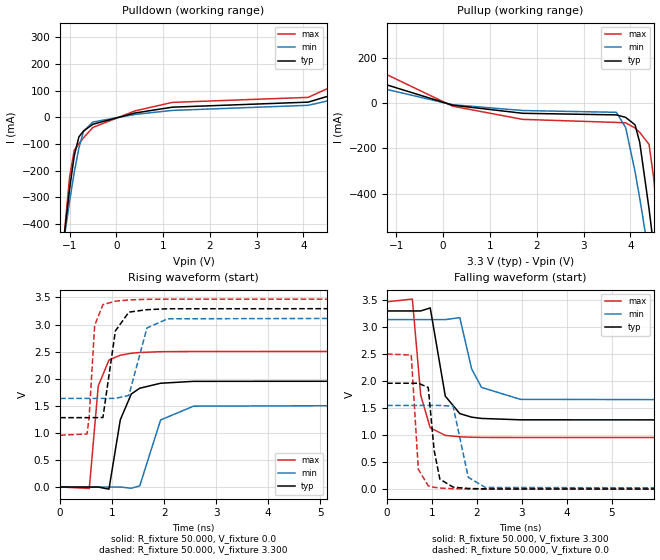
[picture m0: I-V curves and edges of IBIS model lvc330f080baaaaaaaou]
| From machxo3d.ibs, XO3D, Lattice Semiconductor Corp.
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|   Model lvc330f080baaaaaaaou
[Model] lvc330f080baaaaaaaou
Model_type Output
Polarity   Non-Inverting
Enable   Active-High
Vmeas =  1.650V
Cref =  0.0F
Rref =  1.000M
Vref =  0.0V
C_comp   4.200pF   3.800pF   7.500pF
[Temperature Range]   25.000   0.105k   -40.000
[Voltage Range]   3.300V   3.140V   3.470V
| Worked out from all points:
|   slope of the pulldown table from 0 to 0.495 V, typ, clamps not added: 24.3 ohm
|   slope of the pullup table from 0 to 0.495 V, typ, clamps not added: 26.6 ohm
|   rising waveform, R_fixture 50.000, V_fixture 0.0: 20-80 % time 242ps typ, 323ps min, 146ps max; typ from 0.002 V to 1.96 V
|   rising waveform, R_fixture 50.000, V_fixture 3.300: 20-80 % time 155ps typ, 230ps min, 93.1ps max; typ from 1.28 V to 3.3 V
|   falling waveform, R_fixture 50.000, V_fixture 3.300: 20-80 % time 267ps typ, 327ps min, 187ps max; typ from 3.3 V to 1.28 V
|   falling waveform, R_fixture 50.000, V_fixture 0.0: 20-80 % time 135ps typ, 200ps min, 93.7ps max; typ from 1.96 V to 0.002 V
[Pulldown]
|Voltage   I(typ)   I(min)   I(max)
-3.3V     -4.507A    -3.482A    -6.263A
-1.1V     -423.4mA   -437.5mA   -416.7mA
-1V       -269.7mA   -316.9mA   -225.2mA
-900mV    -144.5mA   -206.8mA   -123.1mA
-800mV    -72.93mA   -115.2mA   -98.46mA
-700mV    -50.75mA   -52.06mA   -75.94mA
-500mV    -25.39mA   -17.08mA   -37.33mA
400mV     16.79mA    11.47mA    24.72mA
1.2V      38.66mA    26.45mA    56.57mA
4.1V      57.51mA    45.64mA    75.36mA
5.4V      125.7mA    96.54mA    179.1mA
6.6V      225.9mA    165.1mA    339.4mA
[Pullup]
|Voltage   I(typ)   I(min)   I(max)
-3.3V     216.1mA    162.8mA    336.4mA
200mV     -8.108mA   -6.066mA   -12.58mA
1.7V      -44.15mA   -31.81mA   -71.17mA
3.7V      -51.26mA   -39.86mA   -84.66mA
3.9V      -62.3mA    -107.4mA   -86.52mA
4.1V      -95.17mA   -302.3mA   -109.5mA
4.2V      -172.6mA   -421.2mA   -128.8mA
4.4V      -468.9mA   -676.6mA   -181.9mA
4.5V      -639.3mA   -809mA     -333.7mA
4.6V      -815.4mA   -943.4mA   -557.7mA
4.7V      -994.9mA   -1.079A    -803mA
6.6V      -4.562A    -3.748A    -5.893A
[Ramp]
| variable   typ   min   max
dV/dt_r   1.176/0.241n   0.930/0.324n   1.501/0.146n
dV/dt_f   1.211/0.270n   0.902/0.331n   1.507/0.188n
R_load = 50.000
[Rising Waveform]
R_fixture= 50.000
V_fixture= 0.0
V_fixture_min= 0.0
V_fixture_max= 0.0
|time   V(typ)   V(min)   V(max)
0s        2.128mV    1.725mV    2.736mV
561ps     2.168mV    1.719mV    -23.14mV
733ps     2.356mV    1.719mV    1.866V
939ps     -37.16mV   1.789mV    2.346V
1.158ns   1.245V     1.975mV    2.434V
1.369ns   1.719V     -19.92mV   2.471V
1.531ns   1.825V     22.59mV    2.484V
1.933ns   1.917V     1.24V      2.499V
2.566ns   1.952V     1.494V     2.503V
20ns      1.962V     1.551V     2.504V
[Rising Waveform]
R_fixture= 50.000
V_fixture= 3.300
V_fixture_min= 3.140
V_fixture_max= 3.470
|time   V(typ)   V(min)   V(max)
0s        1.282V     1.637V     957.6mV
517ps     1.282V     1.637V     981.4mV
558ps     1.282V     1.637V     1.291V
664ps     1.283V     1.637V     2.983V
823ps     1.285V     1.637V     3.367V
1.063ns   2.883V     1.638V     3.431V
1.322ns   3.229V     1.692V     3.454V
1.67ns    3.274V     2.936V     3.465V
2.068ns   3.291V     3.106V     3.468V
20ns      3.3V       3.14V      3.47V
[Falling Waveform]
R_fixture= 50.000
V_fixture= 3.300
V_fixture_min= 3.140
V_fixture_max= 3.470
|time   V(typ)   V(min)   V(max)
0s        3.3V       3.14V      3.47V
563ps     3.3V       3.14V      3.52V
750ps     3.3V       3.14V      1.737V
961ps     3.356V     3.14V      1.136V
1.296ns   1.723V     3.14V      996.7mV
1.619ns   1.4V       3.176V     970.8mV
1.882ns   1.334V     2.227V     962.8mV
2.102ns   1.311V     1.885V     959.8mV
2.966ns   1.285V     1.664V     957.8mV
20ns      1.282V     1.637V     957.6mV
[Falling Waveform]
R_fixture= 50.000
V_fixture= 0.0
V_fixture_min= 0.0
V_fixture_max= 0.0
|time   V(typ)   V(min)   V(max)
0s        1.962V     1.551V     2.504V
539ps     1.962V     1.551V     2.483V
696ps     1.962V     1.551V     369.2mV
917ps     1.883V     1.551V     62.8mV
1.048ns   717.9mV    1.551V     36.47mV
1.175ns   187.3mV    1.551V     22.95mV
1.469ns   39.7mV     1.537V     9.576mV
1.807ns   15.04mV    221.9mV    4.744mV
2.188ns   6.358mV    33.13mV    3.208mV
20ns      2.128mV    1.725mV    2.736mV
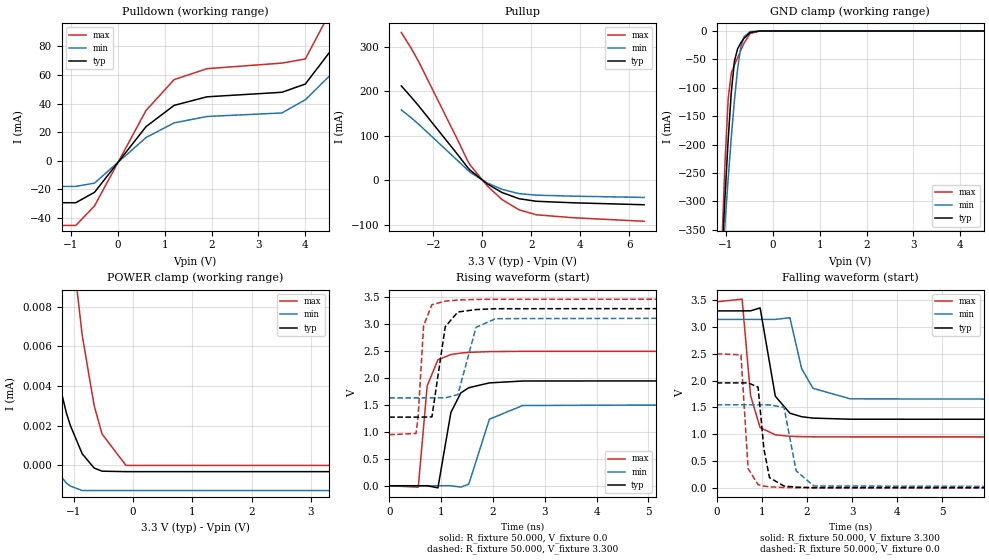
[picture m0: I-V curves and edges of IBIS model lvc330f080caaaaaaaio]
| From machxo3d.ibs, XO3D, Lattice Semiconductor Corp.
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|   Model lvc330f080caaaaaaaio
[Model] lvc330f080caaaaaaaio
Model_type I/O
Polarity   Non-Inverting
Enable   Active-Low
Vinl =  0.800V
Vinh =  2.000V
Vmeas =  1.650V
Cref =  0.0F
Rref =  1.000M
Vref =  0.0V
C_comp   4.200pF   3.800pF   7.500pF
[Temperature Range]   25.000   0.105k   -40.000
[Voltage Range]   3.300V   3.140V   3.470V
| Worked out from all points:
|   slope of the pulldown table from 0 to 0.495 V, typ, clamps not added: 24.3 ohm
|   slope of the pullup table from 0 to 0.495 V, typ, clamps not added: 26.7 ohm
|   GND clamp passes 1 mA (typ) near -0.43 V on its own axis
|   rising waveform, R_fixture 50.000, V_fixture 0.0: 20-80 % time 242ps typ, 324ps min, 147ps max; typ from 0 V to 1.96 V
|   rising waveform, R_fixture 50.000, V_fixture 3.300: 20-80 % time 154ps typ, 231ps min, 93.2ps max; typ from 1.27 V to 3.3 V
|   falling waveform, R_fixture 50.000, V_fixture 3.300: 20-80 % time 265ps typ, 326ps min, 185ps max; typ from 3.3 V to 1.27 V
|   falling waveform, R_fixture 50.000, V_fixture 0.0: 20-80 % time 135ps typ, 199ps min, 93.1ps max; typ from 1.96 V to 0 V
[Pulldown]
|Voltage   I(typ)   I(min)   I(max)
-3.3V     -29.32mA   -17.9mA    -45.21mA
-900mV    -29.32mA   -17.9mA    -45.21mA
-500mV    -22.04mA   -15.61mA   -31.59mA
600mV     23.9mA     16.31mA    35.23mA
1.2V      38.8mA     26.54mA    56.81mA
1.9V      44.78mA    31.02mA    64.46mA
3.5V      47.95mA    33.48mA    68.37mA
4V        53.73mA    42.73mA    71.25mA
4.7V      83.75mA    65.34mA    114.7mA
5.3V      118.2mA    90.44mA    168.1mA
5.9V      161.7mA    120.6mA    237.3mA
6.6V      222.3mA    159.8mA    336.1mA
[Pullup]
|Voltage   I(typ)   I(min)   I(max)
-3.3V     212.3mA    158.2mA    332.3mA
-2.9V     187.3mA    140.6mA    297.2mA
-2.6V     167.8mA    126.4mA    267.5mA
-1V       57.56mA    43.96mA    90.45mA
-600mV    28.98mA    23.04mA    44.04mA
-500mV    22.88mA    18.06mA    34.67mA
200mV     -8.086mA   -6.051mA   -12.55mA
800mV     -27.53mA   -20.35mA   -43.24mA
1.5V      -41.6mA    -30.18mA   -66.6mA
2.2V      -47.32mA   -33.59mA   -77.7mA
3.7V      -50.76mA   -35.84mA   -84.41mA
6.6V      -55.19mA   -38.7mA    -92.41mA
[GND_clamp]
|Voltage   I(typ)   I(min)   I(max)
-3.3V     -4.507A    -3.482A    -6.263A
-1.089V   -398.4mA   -420.6mA   -374.7mA
-1.022V   -290.7mA   -338.6mA   -230.6mA
-955mV    -191.4mA   -260.2mA   -120.1mA
-888mV    -107.5mA   -187mA     -73.7mA
-821mV    -53mA      -121.4mA   -59.85mA
-754mV    -31.41mA   -66.94mA   -47.47mA
-687mV    -21.17mA   -28.82mA   -34.25mA
-620mV    -13.21mA   -10.23mA   -22mA
-486mV    -2.63mA    -1.112mA   -4.479mA
-285mV    -80.91uA   -42.41uA   -152.3uA
6.6V      121.2uA    55.82uA    291.2uA
[POWER_clamp]
|Voltage   I(typ)   I(min)   I(max)
-3.3V     704.7uA    440.9uA    1.167mA
-2.596V   46.79uA    12.42uA    184.2uA
-2.328V   25.67uA    8.107uA    76.87uA
-1.792V   13.09uA    2.762uA    43.68uA
-1.39V    5.98uA     124nA      24.26uA
-1.122V   2.656uA    -886.2nA   13.98uA
-1.055V   2.02uA     -1.042uA   11.85uA
-854mV    585.6nA    -1.267uA   6.557uA
-653mV    -133.8nA   -1.267uA   3.017uA
-519mV    -290.6nA   -1.267uA   1.58uA
-117mV    -313.6nA   -1.267uA   0A
3.3V      -313.6nA   -1.267uA   0A
[Ramp]
| variable   typ   min   max
dV/dt_r   1.174/0.242n   0.928/0.325n   1.499/0.146n
dV/dt_f   1.214/0.269n   0.904/0.330n   1.511/0.187n
R_load = 50.000
[Rising Waveform]
R_fixture= 50.000
V_fixture= 0.0
V_fixture_min= 0.0
V_fixture_max= 0.0
|time   V(typ)   V(min)   V(max)
0s        17.57nV    44.81nV    205.1nV
561ps     41.04uV    -2.964uV   -26.41mV
733ps     143.1uV    -2.964uV   1.857V
940ps     -39.08mV   20.92uV    2.341V
1.19ns    1.361V     147.7uV    2.437V
1.381ns   1.724V     -24.33mV   2.465V
1.535ns   1.821V     28.85mV    2.478V
1.933ns   1.911V     1.236V     2.492V
2.576ns   1.946V     1.491V     2.497V
20ns      1.956V     1.547V     2.498V
[Rising Waveform]
R_fixture= 50.000
V_fixture= 3.300
V_fixture_min= 3.140
V_fixture_max= 3.470
|time   V(typ)   V(min)   V(max)
0s        1.275V     1.632V     949.1mV
517ps     1.275V     1.632V     971.8mV
559ps     1.275V     1.632V     1.292V
664ps     1.276V     1.632V     2.974V
824ps     1.279V     1.632V     3.364V
1.081ns   2.954V     1.634V     3.43V
1.324ns   3.228V     1.691V     3.45V
1.675ns   3.273V     2.942V     3.461V
2.051ns   3.289V     3.104V     3.465V
20ns      3.298V     3.139V     3.467V
[Falling Waveform]
R_fixture= 50.000
V_fixture= 3.300
V_fixture_min= 3.140
V_fixture_max= 3.470
|time   V(typ)   V(min)   V(max)
0s        3.298V     3.139V     3.467V
563ps     3.298V     3.139V     3.517V
751ps     3.299V     3.139V     1.719V
962ps     3.353V     3.139V     1.123V
1.299ns   1.708V     3.139V     988.3mV
1.622ns   1.391V     3.17V      961.4mV
1.881ns   1.326V     2.226V     954.4mV
2.133ns   1.3V       1.855V     951.4mV
2.959ns   1.279V     1.659V     949.4mV
20ns      1.275V     1.632V     949mV
[Falling Waveform]
R_fixture= 50.000
V_fixture= 0.0
V_fixture_min= 0.0
V_fixture_max= 0.0
|time   V(typ)   V(min)   V(max)
0s        1.956V     1.547V     2.498V
538ps     1.956V     1.547V     2.479V
696ps     1.956V     1.547V     360.2mV
917ps     1.877V     1.547V     58.99mV
1.046ns   727.4mV    1.547V     33.07mV
1.17ns    190.4mV    1.546V     19.94mV
1.492ns   33.78mV    1.501V     5.66mV
1.76ns    13.87mV    317.5mV    2.266mV
2.151ns   4.426mV    34.9mV     581.1uV
20ns      22.08nV    83.95nV    -1.426nV
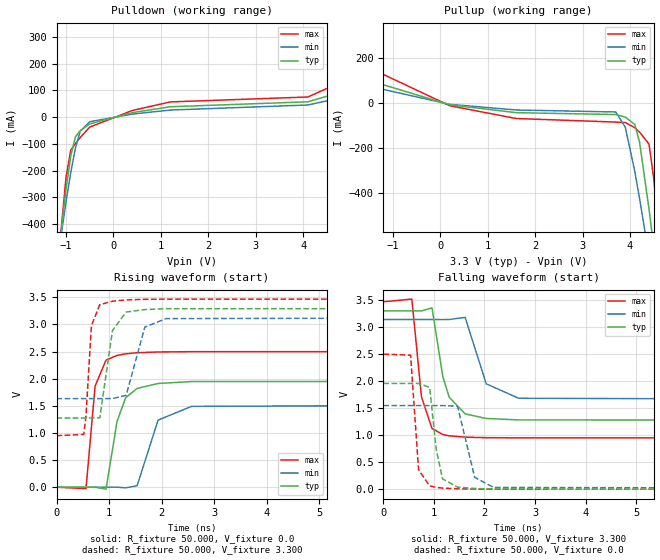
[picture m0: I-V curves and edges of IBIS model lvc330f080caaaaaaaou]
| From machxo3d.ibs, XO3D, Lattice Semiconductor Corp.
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|   Model lvc330f080caaaaaaaou
[Model] lvc330f080caaaaaaaou
Model_type Output
Polarity   Non-Inverting
Enable   Active-High
Vmeas =  1.650V
Cref =  0.0F
Rref =  1.000M
Vref =  0.0V
C_comp   4.200pF   3.800pF   7.500pF
[Temperature Range]   25.000   0.105k   -40.000
[Voltage Range]   3.300V   3.140V   3.470V
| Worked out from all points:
|   slope of the pulldown table from 0 to 0.495 V, typ, clamps not added: 24.2 ohm
|   slope of the pullup table from 0 to 0.495 V, typ, clamps not added: 26.7 ohm
|   rising waveform, R_fixture 50.000, V_fixture 0.0: 20-80 % time 243ps typ, 324ps min, 147ps max; typ from 0 V to 1.96 V
|   rising waveform, R_fixture 50.000, V_fixture 3.300: 20-80 % time 155ps typ, 231ps min, 93.2ps max; typ from 1.27 V to 3.3 V
|   falling waveform, R_fixture 50.000, V_fixture 3.300: 20-80 % time 265ps typ, 326ps min, 185ps max; typ from 3.3 V to 1.27 V
|   falling waveform, R_fixture 50.000, V_fixture 0.0: 20-80 % time 135ps typ, 199ps min, 93.1ps max; typ from 1.96 V to 0 V
[Pulldown]
|Voltage   I(typ)   I(min)   I(max)
-3.3V     -4.507A    -3.482A    -6.263A
-1.1V     -423.4mA   -437.5mA   -416.7mA
-1V       -269.7mA   -316.9mA   -225.2mA
-900mV    -144.5mA   -206.8mA   -123.1mA
-800mV    -72.92mA   -115.2mA   -98.44mA
-700mV    -50.73mA   -52.05mA   -75.91mA
-500mV    -25.36mA   -17.06mA   -37.28mA
400mV     17mA       11.58mA    25.12mA
1.2V      38.9mA     26.58mA    57.05mA
4.1V      57.52mA    45.55mA    75.45mA
5.4V      125mA      95.19mA    178.8mA
6.6V      223.2mA    160.5mA    337.3mA
[Pullup]
|Voltage   I(typ)   I(min)   I(max)
-3.3V     213.1mA    158.7mA    333.8mA
200mV     -7.98mA    -6.011mA   -12.3mA
1.6V      -42.8mA    -30.99mA   -68.66mA
3.7V      -51.21mA   -39.84mA   -84.53mA
3.9V      -62.28mA   -107.4mA   -86.46mA
4.1V      -95.15mA   -302.3mA   -109.5mA
4.2V      -172.6mA   -421.2mA   -128.8mA
4.4V      -468.8mA   -676.6mA   -181.9mA
4.5V      -639.3mA   -809mA     -333.7mA
4.6V      -815.4mA   -943.4mA   -557.7mA
4.7V      -994.9mA   -1.079A    -803mA
6.6V      -4.562A    -3.748A    -5.893A
[Ramp]
| variable   typ   min   max
dV/dt_r   1.174/0.242n   0.928/0.325n   1.499/0.146n
dV/dt_f   1.214/0.269n   0.904/0.330n   1.511/0.187n
R_load = 50.000
[Rising Waveform]
R_fixture= 50.000
V_fixture= 0.0
V_fixture_min= 0.0
V_fixture_max= 0.0
|time   V(typ)   V(min)   V(max)
0s        17.57nV    44.81nV    205.1nV
561ps     39.01uV    -4.861uV   -26.4mV
734ps     133.6uV    -4.861uV   1.863V
942ps     -36.78mV   102.9uV    2.342V
1.152ns   1.212V     355.3uV    2.428V
1.316ns   1.649V     -11.96mV   2.458V
1.534ns   1.82V      26.5mV     2.478V
1.933ns   1.911V     1.236V     2.492V
2.573ns   1.947V     1.49V      2.497V
20ns      1.956V     1.547V     2.498V
[Rising Waveform]
R_fixture= 50.000
V_fixture= 3.300
V_fixture_min= 3.140
V_fixture_max= 3.470
|time   V(typ)   V(min)   V(max)
0s        1.275V     1.632V     949.1mV
517ps     1.275V     1.632V     971.8mV
559ps     1.275V     1.632V     1.292V
664ps     1.276V     1.632V     2.974V
823ps     1.278V     1.632V     3.363V
1.065ns   2.888V     1.633V     3.428V
1.325ns   3.228V     1.693V     3.451V
1.681ns   3.273V     2.951V     3.462V
2.087ns   3.289V     3.107V     3.466V
20ns      3.298V     3.139V     3.467V
[Falling Waveform]
R_fixture= 50.000
V_fixture= 3.300
V_fixture_min= 3.140
V_fixture_max= 3.470
|time   V(typ)   V(min)   V(max)
0s        3.298V     3.139V     3.467V
563ps     3.298V     3.139V     3.517V
753ps     3.298V     3.139V     1.708V
962ps     3.353V     3.139V     1.123V
1.176ns   2.082V     3.138V     1.011V
1.303ns   1.7V       3.139V     986.8mV
1.617ns   1.393V     3.178V     962mV
2.035ns   1.308V     1.949V     952mV
2.675ns   1.281V     1.682V     949.3mV
20ns      1.275V     1.632V     949.1mV
[Falling Waveform]
R_fixture= 50.000
V_fixture= 0.0
V_fixture_min= 0.0
V_fixture_max= 0.0
|time   V(typ)   V(min)   V(max)
0s        1.956V     1.547V     2.498V
538ps     1.956V     1.547V     2.479V
696ps     1.956V     1.547V     360.2mV
916ps     1.881V     1.547V     58.69mV
1.044ns   745mV      1.547V     33.42mV
1.17ns    190.4mV    1.546V     20.09mV
1.467ns   37.19mV    1.534V     6.275mV
1.807ns   12.58mV    218.2mV    1.724mV
2.18ns    4.064mV    31.89mV    467.6uV
20ns      -216.8nV   201nV      123.3nV
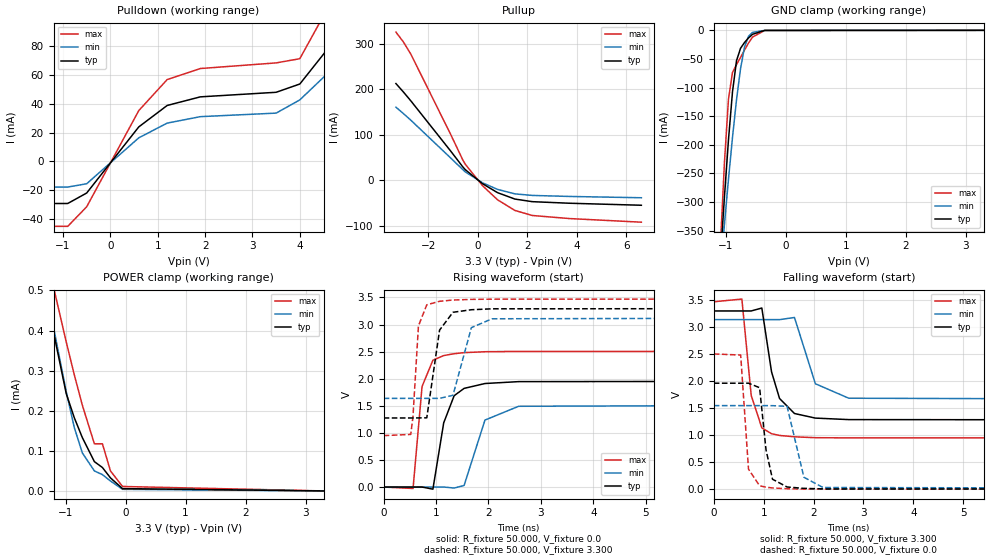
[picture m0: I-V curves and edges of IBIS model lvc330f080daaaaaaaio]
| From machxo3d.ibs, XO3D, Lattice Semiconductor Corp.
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|   Model lvc330f080daaaaaaaio
[Model] lvc330f080daaaaaaaio
Model_type I/O
Polarity   Non-Inverting
Enable   Active-Low
Vinl =  0.800V
Vinh =  2.000V
Vmeas =  1.650V
Cref =  0.0F
Rref =  1.000M
Vref =  0.0V
C_comp   4.200pF   3.800pF   7.500pF
[Temperature Range]   25.000   0.105k   -40.000
[Voltage Range]   3.300V   3.140V   3.470V
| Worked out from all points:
|   slope of the pulldown table from 0 to 0.495 V, typ, clamps not added: 24.3 ohm
|   slope of the pullup table from 0 to 0.495 V, typ, clamps not added: 26.7 ohm
|   GND clamp passes 1 mA (typ) near -0.43 V on its own axis
|   POWER clamp passes 1 mA (typ) near -1.85 V on its own axis
|   rising waveform, R_fixture 50.000, V_fixture 0.0: 20-80 % time 244ps typ, 324ps min, 148ps max; typ from 0 V to 1.96 V
|   rising waveform, R_fixture 50.000, V_fixture 3.300: 20-80 % time 155ps typ, 230ps min, 93.4ps max; typ from 1.27 V to 3.3 V
|   falling waveform, R_fixture 50.000, V_fixture 3.300: 20-80 % time 268ps typ, 327ps min, 189ps max; typ from 3.3 V to 1.27 V
|   falling waveform, R_fixture 50.000, V_fixture 0.0: 20-80 % time 136ps typ, 199ps min, 93.9ps max; typ from 1.96 V to 0 V
[Pulldown]
|Voltage   I(typ)   I(min)   I(max)
-3.3V     -29.32mA   -17.9mA    -45.21mA
-900mV    -29.32mA   -17.9mA    -45.21mA
-500mV    -22.04mA   -15.61mA   -31.59mA
600mV     23.9mA     16.31mA    35.23mA
1.2V      38.8mA     26.54mA    56.81mA
1.9V      44.78mA    31.02mA    64.46mA
3.5V      47.95mA    33.48mA    68.37mA
4V        53.7mA     42.66mA    71.29mA
4.6V      78.57mA    61.48mA    107.1mA
5.3V      117.8mA    90.48mA    167.4mA
5.9V      161.5mA    121.2mA    236.5mA
6.6V      222.1mA    162.3mA    332.3mA
[Pullup]
|Voltage   I(typ)   I(min)   I(max)
-3.3V     212.2mA    160.3mA    325.3mA
-3V       193.8mA    146.3mA    303.7mA
-2.7V     174.3mA    131.8mA    277mA
-1.1V     64.48mA    49.08mA    101.4mA
-600mV    28.97mA    23.03mA    44.05mA
-500mV    22.89mA    18.05mA    34.72mA
200mV     -8.086mA   -6.051mA   -12.55mA
800mV     -27.53mA   -20.35mA   -43.24mA
1.5V      -41.6mA    -30.18mA   -66.6mA
2.2V      -47.32mA   -33.59mA   -77.7mA
3.7V      -50.76mA   -35.84mA   -84.41mA
6.6V      -55.19mA   -38.7mA    -92.41mA
[GND_clamp]
|Voltage   I(typ)   I(min)   I(max)
-3.3V     -4.507A    -3.482A    -6.263A
-1.089V   -398.4mA   -420.6mA   -374.7mA
-1.022V   -290.7mA   -338.6mA   -230.6mA
-955mV    -191.4mA   -260.2mA   -120.1mA
-888mV    -107.5mA   -187mA     -73.7mA
-821mV    -53mA      -121.4mA   -59.85mA
-754mV    -31.41mA   -66.94mA   -47.47mA
-687mV    -21.17mA   -28.82mA   -34.25mA
-620mV    -13.21mA   -10.23mA   -22mA
-553mV    -6.875mA   -3.578mA   -11.73mA
-352mV    -176.3uA   -89.98uA   -279uA
3.3V      50.87nA    0A         -26.43uA
[POWER_clamp]
|Voltage   I(typ)   I(min)   I(max)
-3.3V     3.967mA    2.512mA    11.53mA
-1.323V   507.3uA    506.4uA    605.6uA
-1.256V   446.6uA    452.8uA    548.7uA
-1.189V   387.7uA    399.8uA    501.1uA
-988mV    242.5uA    247.5uA    371.4uA
-854mV    182.6uA    158.2uA    289.7uA
-720mV    133.1uA    94.82uA    213.9uA
-519mV    73.06uA    49.89uA    117.5uA
-385mV    58.36uA    40.66uA    117.5uA
-251mV    32.53uA    24.74uA    49.87uA
-50mV     5.761uA    3.987uA    11.09uA
3.3V      0A         0A         0A
[Ramp]
| variable   typ   min   max
dV/dt_r   1.177/0.244n   0.928/0.325n   1.503/0.147n
dV/dt_f   1.215/0.273n   0.902/0.331n   1.513/0.190n
R_load = 50.000
[Rising Waveform]
R_fixture= 50.000
V_fixture= 0.0
V_fixture_min= 0.0
V_fixture_max= 0.0
|time   V(typ)   V(min)   V(max)
0s        17.57nV    44.81nV    205.1nV
561ps     41.03uV    -2.898uV   -26.41mV
733ps     143.1uV    -2.898uV   1.857V
940ps     -39.08mV   20.91uV    2.341V
1.146ns   1.185V     362.9uV    2.427V
1.345ns   1.686V     -18.39mV   2.461V
1.535ns   1.821V     28.85mV    2.481V
1.933ns   1.911V     1.236V     2.498V
2.576ns   1.946V     1.491V     2.504V
20ns      1.962V     1.547V     2.504V
[Rising Waveform]
R_fixture= 50.000
V_fixture= 3.300
V_fixture_min= 3.140
V_fixture_max= 3.470
|time   V(typ)   V(min)   V(max)
0s        1.275V     1.637V     949.1mV
517ps     1.275V     1.637V     971.8mV
559ps     1.275V     1.637V     1.292V
664ps     1.276V     1.637V     2.974V
823ps     1.278V     1.637V     3.363V
1.067ns   2.897V     1.637V     3.429V
1.323ns   3.226V     1.694V     3.452V
1.674ns   3.273V     2.942V     3.464V
2.068ns   3.29V      3.106V     3.468V
20ns      3.3V       3.14V      3.47V
[Falling Waveform]
R_fixture= 50.000
V_fixture= 3.300
V_fixture_min= 3.140
V_fixture_max= 3.470
|time   V(typ)   V(min)   V(max)
0s        3.3V       3.14V      3.47V
563ps     3.3V       3.14V      3.52V
750ps     3.3V       3.14V      1.737V
963ps     3.354V     3.14V      1.134V
1.157ns   2.174V     3.139V     1.027V
1.318ns   1.679V     3.139V     994.5mV
1.617ns   1.401V     3.179V     969.5mV
2.036ns   1.316V     1.952V     953mV
2.705ns   1.288V     1.684V     949.7mV
20ns      1.275V     1.637V     949mV
[Falling Waveform]
R_fixture= 50.000
V_fixture= 0.0
V_fixture_min= 0.0
V_fixture_max= 0.0
|time   V(typ)   V(min)   V(max)
0s        1.962V     1.547V     2.504V
539ps     1.962V     1.547V     2.483V
696ps     1.962V     1.547V     369.2mV
918ps     1.879V     1.547V     63.11mV
1.047ns   726.5mV    1.547V     36.63mV
1.177ns   184.1mV    1.546V     22.47mV
1.469ns   40.41mV    1.533V     7.796mV
1.806ns   14.91mV    220.1mV    2.101mV
2.189ns   5.255mV    30.58mV    641.8uV
20ns      -122nV     83.95nV    41.95nV
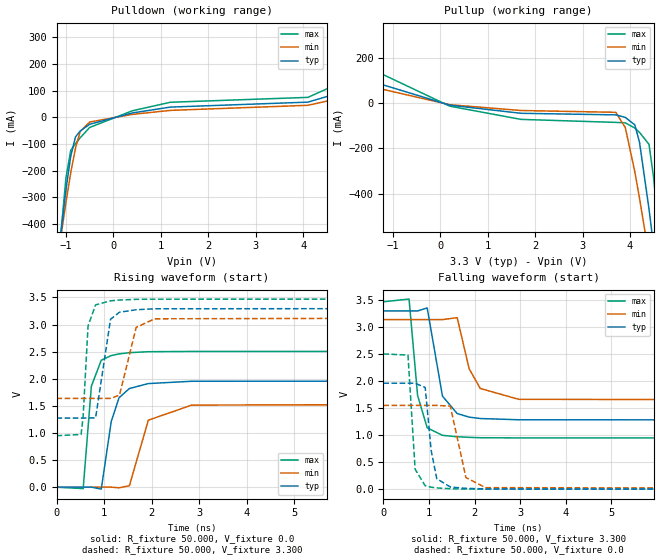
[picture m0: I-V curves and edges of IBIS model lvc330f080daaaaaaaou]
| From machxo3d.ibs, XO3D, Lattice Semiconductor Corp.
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|   Model lvc330f080daaaaaaaou
[Model] lvc330f080daaaaaaaou
Model_type Output
Polarity   Non-Inverting
Enable   Active-High
Vmeas =  1.650V
Cref =  0.0F
Rref =  1.000M
Vref =  0.0V
C_comp   4.200pF   3.800pF   7.500pF
[Temperature Range]   25.000   0.105k   -40.000
[Voltage Range]   3.300V   3.140V   3.470V
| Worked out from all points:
|   slope of the pulldown table from 0 to 0.495 V, typ, clamps not added: 24.2 ohm
|   slope of the pullup table from 0 to 0.495 V, typ, clamps not added: 26.6 ohm
|   rising waveform, R_fixture 50.000, V_fixture 0.0: 20-80 % time 245ps typ, 328ps min, 148ps max; typ from 0 V to 1.96 V
|   rising waveform, R_fixture 50.000, V_fixture 3.300: 20-80 % time 155ps typ, 231ps min, 93.4ps max; typ from 1.27 V to 3.3 V
|   falling waveform, R_fixture 50.000, V_fixture 3.300: 20-80 % time 270ps typ, 328ps min, 189ps max; typ from 3.3 V to 1.27 V
|   falling waveform, R_fixture 50.000, V_fixture 0.0: 20-80 % time 136ps typ, 200ps min, 93.9ps max; typ from 1.96 V to 0 V
[Pulldown]
|Voltage   I(typ)   I(min)   I(max)
-3.3V     -4.507A    -3.482A    -6.263A
-1.1V     -423.4mA   -437.5mA   -416.7mA
-1V       -269.7mA   -316.9mA   -225.2mA
-900mV    -144.5mA   -206.8mA   -123.1mA
-800mV    -72.92mA   -115.2mA   -98.44mA
-700mV    -50.73mA   -52.05mA   -75.91mA
-500mV    -25.36mA   -17.06mA   -37.28mA
400mV     17mA       11.58mA    25.12mA
1.2V      38.9mA     26.58mA    57.05mA
4.1V      57.51mA    45.64mA    75.36mA
5.4V      125.7mA    96.54mA    179.1mA
6.6V      225.9mA    165.1mA    339.4mA
[Pullup]
|Voltage   I(typ)   I(min)   I(max)
-3.3V     216.1mA    162.8mA    336.4mA
200mV     -8.108mA   -6.066mA   -12.58mA
1.7V      -44.15mA   -31.81mA   -71.17mA
3.7V      -51.21mA   -39.84mA   -84.53mA
3.9V      -62.28mA   -107.4mA   -86.46mA
4.1V      -95.15mA   -302.3mA   -109.5mA
4.2V      -172.6mA   -421.2mA   -128.8mA
4.4V      -468.8mA   -676.6mA   -181.9mA
4.5V      -639.3mA   -809mA     -333.7mA
4.6V      -815.4mA   -943.4mA   -557.7mA
4.7V      -994.9mA   -1.079A    -803mA
6.6V      -4.562A    -3.748A    -5.893A
[Ramp]
| variable   typ   min   max
dV/dt_r   1.177/0.244n   0.931/0.327n   1.503/0.147n
dV/dt_f   1.215/0.273n   0.902/0.331n   1.513/0.190n
R_load = 50.000
[Rising Waveform]
R_fixture= 50.000
V_fixture= 0.0
V_fixture_min= 0.0
V_fixture_max= 0.0
|time   V(typ)   V(min)   V(max)
0s        17.57nV    44.81nV    205.1nV
561ps     38.97uV    -4.802uV   -26.4mV
734ps     133.6uV    -4.802uV   1.863V
942ps     -36.78mV   102.9uV    2.342V
1.152ns   1.212V     355.4uV    2.428V
1.316ns   1.649V     -11.96mV   2.458V
1.534ns   1.82V      26.5mV     2.481V
1.933ns   1.911V     1.236V     2.499V
2.846ns   1.954V     1.514V     2.504V
20ns      1.962V     1.551V     2.504V
[Rising Waveform]
R_fixture= 50.000
V_fixture= 3.300
V_fixture_min= 3.140
V_fixture_max= 3.470
|time   V(typ)   V(min)   V(max)
0s        1.275V     1.637V     949.1mV
517ps     1.275V     1.637V     971.8mV
559ps     1.275V     1.637V     1.292V
664ps     1.276V     1.637V     2.974V
823ps     1.278V     1.637V     3.363V
1.137ns   3.097V     1.638V     3.438V
1.324ns   3.227V     1.696V     3.452V
1.678ns   3.273V     2.948V     3.465V
2.068ns   3.291V     3.106V     3.468V
20ns      3.3V       3.14V      3.47V
[Falling Waveform]
R_fixture= 50.000
V_fixture= 3.300
V_fixture_min= 3.140
V_fixture_max= 3.470
|time   V(typ)   V(min)   V(max)
0s        3.3V       3.14V      3.47V
563ps     3.3V       3.14V      3.52V
750ps     3.3V       3.14V      1.737V
961ps     3.356V     3.14V      1.136V
1.296ns   1.723V     3.14V      996.7mV
1.619ns   1.4V       3.176V     970.2mV
1.882ns   1.334V     2.227V     959.7mV
2.126ns   1.308V     1.865V     952.6mV
2.966ns   1.285V     1.664V     949.2mV
20ns      1.275V     1.637V     949mV
[Falling Waveform]
R_fixture= 50.000
V_fixture= 0.0
V_fixture_min= 0.0
V_fixture_max= 0.0
|time   V(typ)   V(min)   V(max)
0s        1.962V     1.551V     2.504V
539ps     1.962V     1.551V     2.483V
696ps     1.962V     1.551V     369.2mV
917ps     1.883V     1.551V     62.8mV
1.048ns   717.9mV    1.551V     36.47mV
1.171ns   193.9mV    1.551V     23.17mV
1.469ns   39.7mV     1.537V     8.023mV
1.811ns   15.04mV    215.3mV    2.211mV
2.24ns    4.877mV    28.41mV    567.3uV
20ns      67.01nV    180.7nV    118.1nV
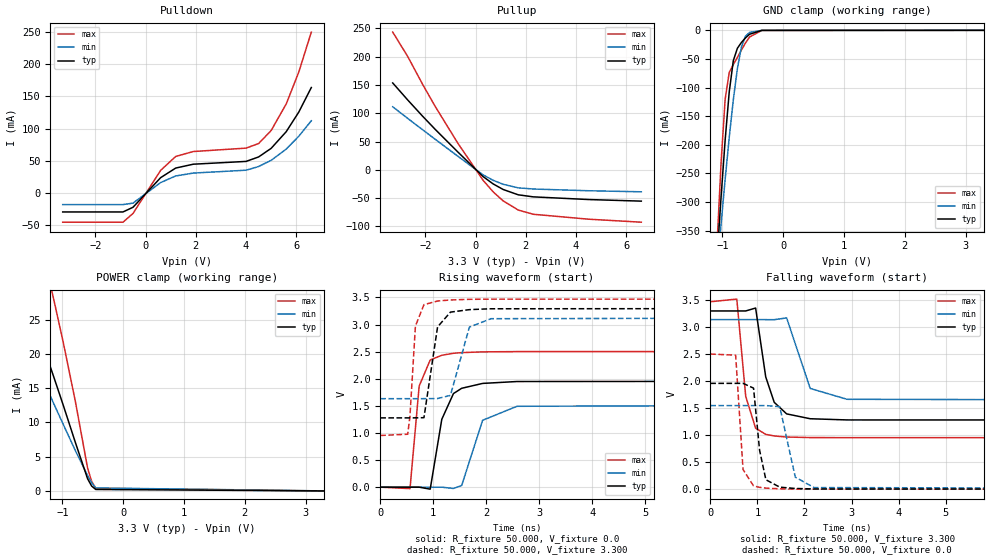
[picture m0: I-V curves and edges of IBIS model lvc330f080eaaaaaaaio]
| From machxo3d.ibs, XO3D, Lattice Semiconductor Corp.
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|   Model lvc330f080eaaaaaaaio
[Model] lvc330f080eaaaaaaaio
Model_type I/O
Polarity   Non-Inverting
Enable   Active-Low
Vinl =  0.800V
Vinh =  2.000V
Vmeas =  1.650V
Cref =  0.0F
Rref =  1.000M
Vref =  0.0V
C_comp   4.200pF   3.800pF   7.500pF
[Temperature Range]   25.000   0.105k   -40.000
[Voltage Range]   3.300V   3.140V   3.470V
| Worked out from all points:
|   slope of the pulldown table from 0 to 0.495 V, typ, clamps not added: 24.3 ohm
|   slope of the pullup table from 0 to 0.495 V, typ, clamps not added: 26.7 ohm
|   GND clamp passes 1 mA (typ) near -0.43 V on its own axis
|   POWER clamp passes 1 mA (typ) near -0.54 V on its own axis
|   rising waveform, R_fixture 50.000, V_fixture 0.0: 20-80 % time 241ps typ, 325ps min, 147ps max; typ from 0 V to 1.96 V
|   rising waveform, R_fixture 50.000, V_fixture 3.300: 20-80 % time 155ps typ, 231ps min, 93.1ps max; typ from 1.28 V to 3.3 V
|   falling waveform, R_fixture 50.000, V_fixture 3.300: 20-80 % time 265ps typ, 333ps min, 186ps max; typ from 3.3 V to 1.28 V
|   falling waveform, R_fixture 50.000, V_fixture 0.0: 20-80 % time 135ps typ, 200ps min, 93.5ps max; typ from 1.96 V to 0 V
[Pulldown]
|Voltage   I(typ)   I(min)   I(max)
-3.3V     -29.32mA   -17.9mA    -45.21mA
-900mV    -29.32mA   -17.9mA    -45.21mA
-500mV    -22.04mA   -15.61mA   -31.59mA
600mV     23.9mA     16.31mA    35.23mA
1.2V      38.8mA     26.54mA    56.81mA
1.9V      44.78mA    31.02mA    64.46mA
4V        49.1mA     35.45mA    69.72mA
4.5V      56.03mA    41.15mA    76.83mA
5V        69.38mA    50.78mA    97mA
5.6V      95.22mA    68.23mA    138.3mA
6.1V      125.6mA    88.08mA    187.6mA
6.6V      163.8mA    112.2mA    249.8mA
[Pullup]
|Voltage   I(typ)   I(min)   I(max)
-3.3V     153.7mA    111.6mA    243.6mA
-2.7V     123.5mA    90.98mA    200.3mA
-2.1V     94.47mA    70.64mA    150.5mA
-1.6V     71.33mA    53.89mA    111.6mA
-700mV    31.42mA    23.96mA    46.76mA
300mV     -11.82mA   -8.831mA   -18.38mA
700mV     -24.77mA   -18.36mA   -38.83mA
1.1V      -34.65mA   -25.44mA   -54.83mA
1.7V      -44.02mA   -31.73mA   -70.96mA
2.3V      -47.65mA   -33.78mA   -78.43mA
4.5V      -52.36mA   -36.84mA   -87.09mA
6.6V      -55.19mA   -38.7mA    -92.41mA
[GND_clamp]
|Voltage   I(typ)   I(min)   I(max)
-3.3V     -4.507A    -3.482A    -6.263A
-1.089V   -398.4mA   -420.6mA   -374.7mA
-1.022V   -290.7mA   -338.6mA   -230.6mA
-955mV    -191.3mA   -260.2mA   -120mA
-888mV    -107.5mA   -187mA     -73.64mA
-821mV    -52.96mA   -121.4mA   -59.79mA
-754mV    -31.36mA   -66.92mA   -47.4mA
-687mV    -21.12mA   -28.79mA   -34.18mA
-620mV    -13.16mA   -10.19mA   -21.93mA
-553mV    -6.814mA   -3.53mA    -11.64mA
-352mV    -96.36uA   -46.21uA   -149.8uA
3.3V      0A         0A         0A
[POWER_clamp]
|Voltage   I(typ)   I(min)   I(max)
-3.3V     59.07mA    46.89mA    89.53mA
-1.993V   37.2mA     28.86mA    58.21mA
-1.926V   35.72mA    27.66mA    56.06mA
-1.591V   27.93mA    21.43mA    44.68mA
-1.189V   17.86mA    13.66mA    29.77mA
-1.122V   16.11mA    12.35mA    27.14mA
-988mV    12.56mA    9.745mA    21.76mA
-787mV    7.078mA    5.887mA    13.07mA
-586mV    1.773mA    2.247mA    3.338mA
-519mV    707uA      1.205mA    1.383mA
-452mV    214.8uA    435.5uA    392.3uA
3.3V      0A         0A         0A
[Ramp]
| variable   typ   min   max
dV/dt_r   1.175/0.242n   0.929/0.325n   1.501/0.146n
dV/dt_f   1.213/0.269n   0.904/0.330n   1.510/0.188n
R_load = 50.000
[Rising Waveform]
R_fixture= 50.000
V_fixture= 0.0
V_fixture_min= 0.0
V_fixture_max= 0.0
|time   V(typ)   V(min)   V(max)
0s        17.95nV    45.29nV    212.7nV
561ps     41.14uV    -2.931uV   -26.47mV
734ps     156.1uV    -2.931uV   1.866V
942ps     -36.85mV   20.99uV    2.346V
1.161ns   1.253V     262.2uV    2.433V
1.381ns   1.727V     -24.13mV   2.47V
1.536ns   1.824V     31.19mV    2.482V
1.931ns   1.914V     1.234V     2.496V
2.58ns    1.949V     1.492V     2.501V
20ns      1.959V     1.548V     2.502V
[Rising Waveform]
R_fixture= 50.000
V_fixture= 3.300
V_fixture_min= 3.140
V_fixture_max= 3.470
|time   V(typ)   V(min)   V(max)
0s        1.278V     1.633V     953.3mV
517ps     1.278V     1.633V     976.5mV
559ps     1.278V     1.633V     1.298V
663ps     1.279V     1.633V     2.971V
824ps     1.282V     1.633V     3.367V
1.081ns   2.956V     1.635V     3.434V
1.324ns   3.229V     1.693V     3.453V
1.681ns   3.275V     2.952V     3.465V
2.088ns   3.291V     3.108V     3.468V
20ns      3.3V       3.14V      3.47V
[Falling Waveform]
R_fixture= 50.000
V_fixture= 3.300
V_fixture_min= 3.140
V_fixture_max= 3.470
|time   V(typ)   V(min)   V(max)
0s        3.3V       3.14V      3.47V
563ps     3.3V       3.14V      3.52V
753ps     3.3V       3.14V      1.716V
963ps     3.354V     3.14V      1.128V
1.178ns   2.077V     3.139V     1.015V
1.358ns   1.608V     3.138V     984.9mV
1.622ns   1.394V     3.171V     965.7mV
2.122ns   1.304V     1.865V     955.5mV
2.904ns   1.282V     1.664V     953.4mV
20ns      1.278V     1.633V     953.2mV
[Falling Waveform]
R_fixture= 50.000
V_fixture= 0.0
V_fixture_min= 0.0
V_fixture_max= 0.0
|time   V(typ)   V(min)   V(max)
0s        1.959V     1.548V     2.502V
539ps     1.959V     1.548V     2.481V
696ps     1.959V     1.548V     364.6mV
919ps     1.871V     1.548V     59.86mV
1.047ns   722mV      1.548V     33.73mV
1.181ns   174.7mV    1.548V     19.4mV
1.476ns   37.08mV    1.527V     6.504mV
1.805ns   12.83mV    222.7mV    1.833mV
2.203ns   3.867mV    29.43mV    527.7uV
20ns      -7.76nV    -5.929nV   226.5nV
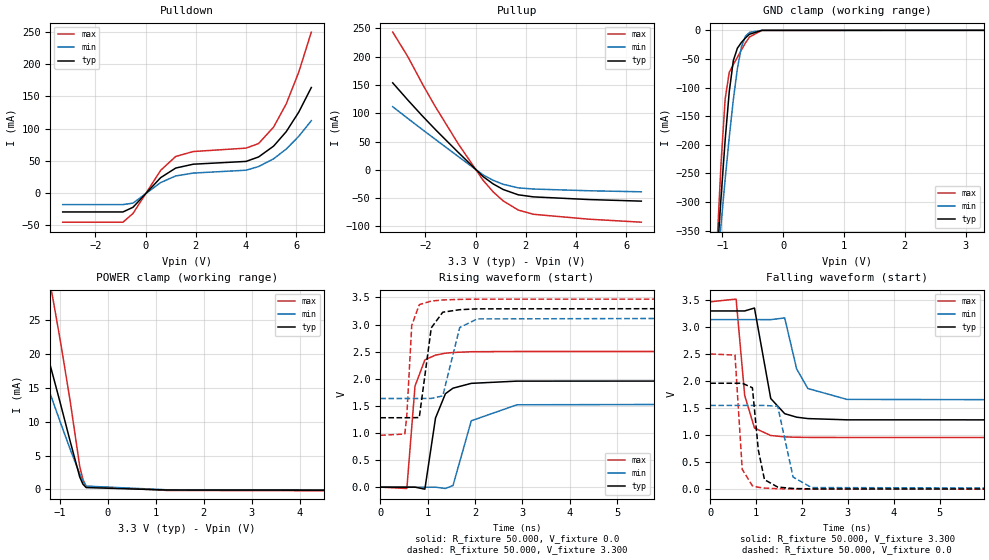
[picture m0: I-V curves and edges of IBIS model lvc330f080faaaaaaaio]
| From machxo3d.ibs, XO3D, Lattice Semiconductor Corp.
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|   Model lvc330f080faaaaaaaio
[Model] lvc330f080faaaaaaaio
Model_type I/O
Polarity   Non-Inverting
Enable   Active-Low
Vinl =  0.800V
Vinh =  2.000V
Vmeas =  1.650V
Cref =  0.0F
Rref =  1.000M
Vref =  0.0V
C_comp   4.200pF   3.800pF   7.500pF
[Temperature Range]   25.000   0.105k   -40.000
[Voltage Range]   3.300V   3.140V   3.470V
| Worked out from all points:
|   slope of the pulldown table from 0 to 0.495 V, typ, clamps not added: 24.3 ohm
|   slope of the pullup table from 0 to 0.495 V, typ, clamps not added: 26.7 ohm
|   GND clamp passes 1 mA (typ) near -0.43 V on its own axis
|   POWER clamp passes 1 mA (typ) near -0.53 V on its own axis
|   rising waveform, R_fixture 50.000, V_fixture 0.0: 20-80 % time 243ps typ, 326ps min, 146ps max; typ from 0.002 V to 1.96 V
|   rising waveform, R_fixture 50.000, V_fixture 3.300: 20-80 % time 155ps typ, 230ps min, 93.1ps max; typ from 1.28 V to 3.3 V
|   falling waveform, R_fixture 50.000, V_fixture 3.300: 20-80 % time 266ps typ, 328ps min, 187ps max; typ from 3.3 V to 1.28 V
|   falling waveform, R_fixture 50.000, V_fixture 0.0: 20-80 % time 135ps typ, 200ps min, 93.7ps max; typ from 1.96 V to 0.002 V
[Pulldown]
|Voltage   I(typ)   I(min)   I(max)
-3.3V     -29.32mA   -17.9mA    -45.21mA
-900mV    -29.32mA   -17.9mA    -45.21mA
-500mV    -22.04mA   -15.61mA   -31.59mA
600mV     23.9mA     16.31mA    35.23mA
1.2V      38.8mA     26.54mA    56.81mA
1.9V      44.78mA    31.02mA    64.46mA
4V        49.1mA     35.45mA    69.72mA
4.5V      56.03mA    41.15mA    76.83mA
5.1V      72.91mA    53.22mA    102.5mA
5.6V      95.22mA    68.23mA    138.3mA
6.1V      125.6mA    88.09mA    187.6mA
6.6V      163.8mA    112.3mA    249.8mA
[Pullup]
|Voltage   I(typ)   I(min)   I(max)
-3.3V     153.9mA    111.7mA    243.6mA
-2.7V     123.6mA    91.02mA    200.3mA
-2.1V     94.5mA     70.65mA    150.5mA
-1.6V     71.34mA    53.9mA     111.6mA
-700mV    31.42mA    23.96mA    46.76mA
300mV     -11.82mA   -8.831mA   -18.38mA
700mV     -24.77mA   -18.36mA   -38.83mA
1.1V      -34.65mA   -25.44mA   -54.83mA
1.7V      -44.02mA   -31.73mA   -70.96mA
2.3V      -47.65mA   -33.78mA   -78.43mA
4.5V      -52.35mA   -36.84mA   -87.06mA
6.6V      -55.19mA   -38.7mA    -92.41mA
[GND_clamp]
|Voltage   I(typ)   I(min)   I(max)
-3.3V     -4.506A    -3.482A    -6.262A
-1.089V   -398.3mA   -420.5mA   -374.5mA
-1.022V   -290.6mA   -338.5mA   -230.4mA
-955mV    -191.2mA   -260.1mA   -119.8mA
-888mV    -107.4mA   -186.9mA   -73.47mA
-821mV    -52.87mA   -121.3mA   -59.62mA
-754mV    -31.28mA   -66.86mA   -47.24mA
-687mV    -21.04mA   -28.74mA   -34.02mA
-620mV    -13.09mA   -10.15mA   -21.79mA
-553mV    -6.755mA   -3.505mA   -11.52mA
-352mV    -90.18uA   -45.39uA   -119.9uA
3.3V      0A         0A         0A
[POWER_clamp]
|Voltage   I(typ)   I(min)   I(max)
-3.3V     62.1mA     51.02mA    92.7mA
-1.926V   36.35mA    28.59mA    56.55mA
-1.591V   28.28mA    21.98mA    45.01mA
-1.189V   18.03mA    13.9mA     29.96mA
-1.122V   16.26mA    12.55mA    27.31mA
-988mV    12.68mA    9.882mA    21.88mA
-787mV    7.154mA    5.963mA    13.15mA
-586mV    1.819mA    2.29mA     3.395mA
-519mV    748.7uA    1.242mA    1.434mA
-452mV    255.4uA    468.1uA    442.9uA
1.223V    -104.1uA   -69.89uA   -164.8uA
6.6V      -145.9uA   -91.75uA   -251.2uA
[Ramp]
| variable   typ   min   max
dV/dt_r   1.176/0.241n   0.930/0.324n   1.501/0.146n
dV/dt_f   1.211/0.270n   0.902/0.331n   1.507/0.188n
R_load = 50.000
[Rising Waveform]
R_fixture= 50.000
V_fixture= 0.0
V_fixture_min= 0.0
V_fixture_max= 0.0
|time   V(typ)   V(min)   V(max)
0s        2.128mV    1.725mV    2.736mV
561ps     2.17mV     1.721mV    -23.15mV
733ps     2.265mV    1.721mV    1.866V
941ps     -35.02mV   1.795mV    2.348V
1.166ns   1.278V     1.978mV    2.437V
1.375ns   1.725V     -22.48mV   2.472V
1.535ns   1.827V     31.78mV    2.485V
1.921ns   1.916V     1.226V     2.499V
2.886ns   1.957V     1.521V     2.504V
20ns      1.962V     1.551V     2.504V
[Rising Waveform]
R_fixture= 50.000
V_fixture= 3.300
V_fixture_min= 3.140
V_fixture_max= 3.470
|time   V(typ)   V(min)   V(max)
0s        1.282V     1.637V     957.6mV
517ps     1.282V     1.637V     981.4mV
558ps     1.282V     1.637V     1.291V
664ps     1.283V     1.637V     2.983V
823ps     1.285V     1.637V     3.367V
1.076ns   2.939V     1.638V     3.433V
1.319ns   3.228V     1.685V     3.453V
1.676ns   3.274V     2.945V     3.464V
2.047ns   3.29V      3.104V     3.468V
20ns      3.3V       3.14V      3.47V
[Falling Waveform]
R_fixture= 50.000
V_fixture= 3.300
V_fixture_min= 3.140
V_fixture_max= 3.470
|time   V(typ)   V(min)   V(max)
0s        3.3V       3.14V      3.47V
563ps     3.3V       3.14V      3.52V
750ps     3.3V       3.14V      1.737V
963ps     3.354V     3.14V      1.134V
1.318ns   1.679V     3.139V     994.5mV
1.622ns   1.399V     3.171V     970.2mV
1.882ns   1.334V     2.227V     962.3mV
2.126ns   1.308V     1.865V     959.9mV
2.98ns    1.285V     1.663V     957.7mV
20ns      1.282V     1.637V     957.5mV
[Falling Waveform]
R_fixture= 50.000
V_fixture= 0.0
V_fixture_min= 0.0
V_fixture_max= 0.0
|time   V(typ)   V(min)   V(max)
0s        1.962V     1.551V     2.504V
539ps     1.962V     1.551V     2.483V
696ps     1.962V     1.551V     369.2mV
918ps     1.879V     1.551V     63.11mV
1.047ns   726.5mV    1.551V     36.63mV
1.181ns   178mV      1.551V     22.29mV
1.469ns   40.41mV    1.537V     9.409mV
1.805ns   14.92mV    225.5mV    4.649mV
2.208ns   5.948mV    30.79mV    3.298mV
20ns      2.128mV    1.725mV    2.736mV
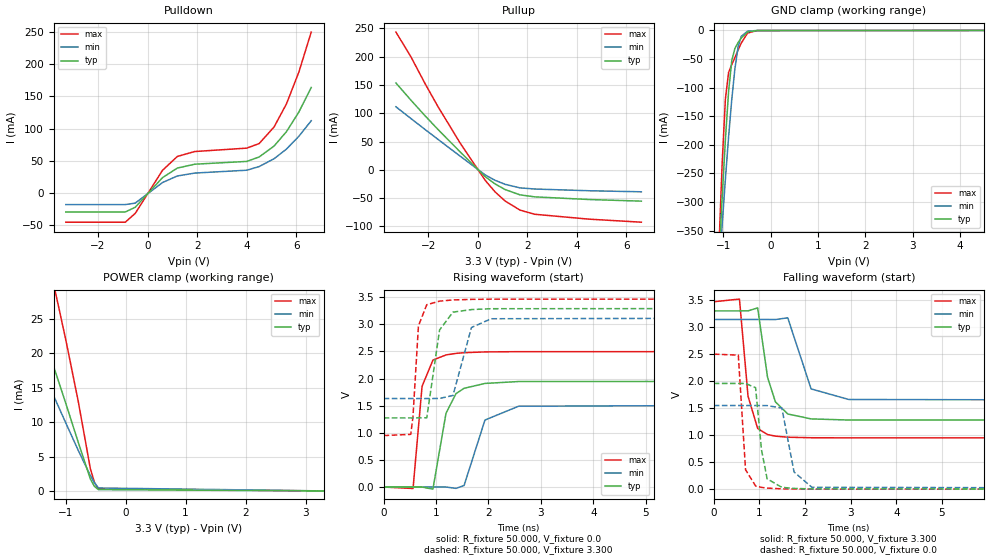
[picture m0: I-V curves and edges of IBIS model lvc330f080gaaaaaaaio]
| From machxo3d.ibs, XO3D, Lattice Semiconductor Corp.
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|   Model lvc330f080gaaaaaaaio
[Model] lvc330f080gaaaaaaaio
Model_type I/O
Polarity   Non-Inverting
Enable   Active-Low
Vinl =  0.800V
Vinh =  2.000V
Vmeas =  1.650V
Cref =  0.0F
Rref =  1.000M
Vref =  0.0V
C_comp   4.200pF   3.800pF   7.500pF
[Temperature Range]   25.000   0.105k   -40.000
[Voltage Range]   3.300V   3.140V   3.470V
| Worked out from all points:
|   slope of the pulldown table from 0 to 0.495 V, typ, clamps not added: 24.3 ohm
|   slope of the pullup table from 0 to 0.495 V, typ, clamps not added: 26.7 ohm
|   GND clamp passes 1 mA (typ) near -0.43 V on its own axis
|   POWER clamp passes 1 mA (typ) near -0.54 V on its own axis
|   rising waveform, R_fixture 50.000, V_fixture 0.0: 20-80 % time 242ps typ, 324ps min, 147ps max; typ from 0 V to 1.96 V
|   rising waveform, R_fixture 50.000, V_fixture 3.300: 20-80 % time 154ps typ, 231ps min, 93.2ps max; typ from 1.27 V to 3.3 V
|   falling waveform, R_fixture 50.000, V_fixture 3.300: 20-80 % time 265ps typ, 326ps min, 185ps max; typ from 3.3 V to 1.27 V
|   falling waveform, R_fixture 50.000, V_fixture 0.0: 20-80 % time 135ps typ, 199ps min, 93.1ps max; typ from 1.96 V to 0 V
[Pulldown]
|Voltage   I(typ)   I(min)   I(max)
-3.3V     -29.32mA   -17.9mA    -45.21mA
-900mV    -29.32mA   -17.9mA    -45.21mA
-500mV    -22.04mA   -15.61mA   -31.59mA
600mV     23.9mA     16.31mA    35.23mA
1.2V      38.8mA     26.54mA    56.81mA
1.9V      44.78mA    31.02mA    64.46mA
4V        49.1mA     35.45mA    69.72mA
4.5V      56.03mA    41.15mA    76.83mA
5.1V      72.91mA    53.22mA    102.5mA
5.6V      95.22mA    68.23mA    138.3mA
6.1V      125.6mA    88.08mA    187.6mA
6.6V      163.8mA    112.2mA    249.8mA
[Pullup]
|Voltage   I(typ)   I(min)   I(max)
-3.3V     153.7mA    111.6mA    243.6mA
-2.7V     123.5mA    90.98mA    200.3mA
-2.1V     94.48mA    70.64mA    150.5mA
-1.6V     71.34mA    53.89mA    111.6mA
-700mV    31.42mA    23.96mA    46.76mA
300mV     -11.82mA   -8.831mA   -18.38mA
700mV     -24.77mA   -18.36mA   -38.83mA
1.1V      -34.65mA   -25.44mA   -54.83mA
1.7V      -44.02mA   -31.73mA   -70.96mA
2.3V      -47.65mA   -33.78mA   -78.43mA
4.5V      -52.35mA   -36.84mA   -87.07mA
6.6V      -55.19mA   -38.7mA    -92.41mA
[GND_clamp]
|Voltage   I(typ)   I(min)   I(max)
-3.3V     -4.507A    -3.482A    -6.263A
-1.089V   -398.4mA   -420.6mA   -374.7mA
-1.022V   -290.7mA   -338.6mA   -230.6mA
-955mV    -191.4mA   -260.2mA   -120.1mA
-888mV    -107.5mA   -187mA     -73.7mA
-821mV    -53mA      -121.4mA   -59.85mA
-754mV    -31.41mA   -66.94mA   -47.47mA
-687mV    -21.17mA   -28.82mA   -34.25mA
-620mV    -13.21mA   -10.23mA   -22mA
-486mV    -2.63mA    -1.112mA   -4.479mA
-285mV    -80.91uA   -42.41uA   -152.3uA
6.6V      121.2uA    55.84uA    291.2uA
[POWER_clamp]
|Voltage   I(typ)   I(min)   I(max)
-3.3V     59.17mA    46.96mA    89.71mA
-1.993V   37.21mA    28.87mA    58.18mA
-1.926V   35.73mA    27.67mA    56.02mA
-1.591V   27.93mA    21.43mA    44.63mA
-1.189V   17.84mA    13.65mA    29.69mA
-1.122V   16.09mA    12.35mA    27.06mA
-988mV    12.53mA    9.74mA     21.66mA
-787mV    7.047mA    5.88mA     12.98mA
-586mV    1.736mA    2.238mA    3.233mA
-519mV    672uA      1.196mA    1.278mA
-452mV    189uA      428.3uA    309.6uA
3.3V      0A         0A         0A
[Ramp]
| variable   typ   min   max
dV/dt_r   1.174/0.242n   0.928/0.325n   1.499/0.146n
dV/dt_f   1.214/0.269n   0.904/0.330n   1.511/0.187n
R_load = 50.000
[Rising Waveform]
R_fixture= 50.000
V_fixture= 0.0
V_fixture_min= 0.0
V_fixture_max= 0.0
|time   V(typ)   V(min)   V(max)
0s        17.57nV    44.81nV    205.1nV
561ps     41.04uV    -2.965uV   -26.41mV
733ps     143.1uV    -2.965uV   1.857V
940ps     -39.08mV   20.91uV    2.341V
1.19ns    1.361V     147.7uV    2.437V
1.381ns   1.724V     -24.33mV   2.465V
1.535ns   1.821V     28.85mV    2.478V
1.933ns   1.911V     1.236V     2.492V
2.576ns   1.946V     1.491V     2.497V
20ns      1.956V     1.547V     2.498V
[Rising Waveform]
R_fixture= 50.000
V_fixture= 3.300
V_fixture_min= 3.140
V_fixture_max= 3.470
|time   V(typ)   V(min)   V(max)
0s        1.275V     1.632V     949.1mV
517ps     1.275V     1.632V     971.8mV
559ps     1.275V     1.632V     1.292V
664ps     1.276V     1.632V     2.974V
823ps     1.278V     1.632V     3.363V
1.067ns   2.897V     1.634V     3.429V
1.323ns   3.226V     1.689V     3.451V
1.675ns   3.273V     2.942V     3.461V
2.051ns   3.289V     3.104V     3.465V
20ns      3.298V     3.139V     3.467V
[Falling Waveform]
R_fixture= 50.000
V_fixture= 3.300
V_fixture_min= 3.140
V_fixture_max= 3.470
|time   V(typ)   V(min)   V(max)
0s        3.298V     3.139V     3.467V
563ps     3.298V     3.139V     3.517V
751ps     3.299V     3.139V     1.719V
962ps     3.353V     3.139V     1.123V
1.179ns   2.069V     3.139V     1.01V
1.351ns   1.615V     3.138V     981.3mV
1.622ns   1.391V     3.17V      961.3mV
2.133ns   1.3V       1.855V     951.3mV
2.959ns   1.279V     1.659V     949.3mV
20ns      1.275V     1.632V     949mV
[Falling Waveform]
R_fixture= 50.000
V_fixture= 0.0
V_fixture_min= 0.0
V_fixture_max= 0.0
|time   V(typ)   V(min)   V(max)
0s        1.956V     1.547V     2.498V
538ps     1.956V     1.547V     2.479V
696ps     1.956V     1.547V     360.2mV
917ps     1.877V     1.547V     58.99mV
1.046ns   727.4mV    1.547V     33.07mV
1.17ns    190.4mV    1.546V     19.94mV
1.492ns   33.78mV    1.501V     5.66mV
1.76ns    13.87mV    317.5mV    2.266mV
2.151ns   4.426mV    34.9mV     581.1uV
20ns      22.08nV    83.95nV    -1.426nV
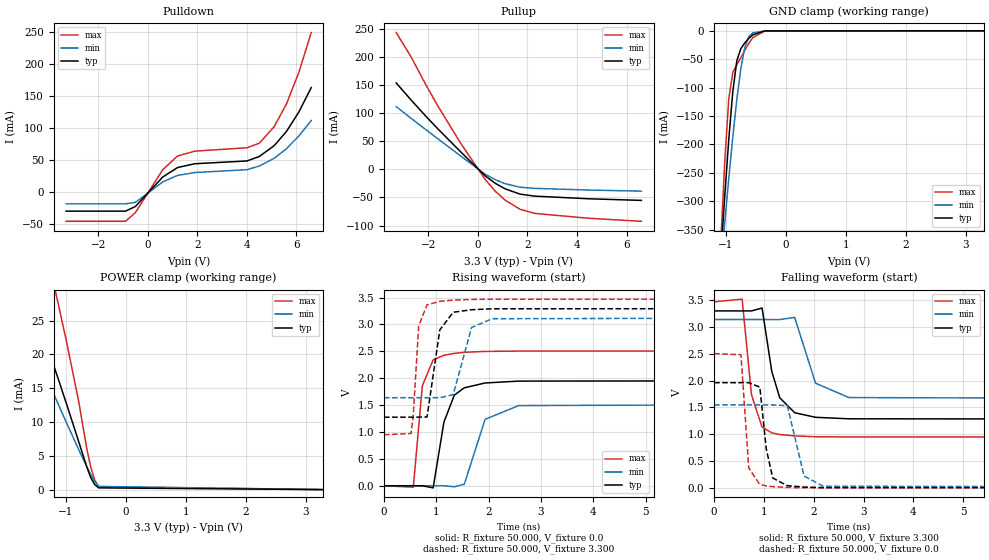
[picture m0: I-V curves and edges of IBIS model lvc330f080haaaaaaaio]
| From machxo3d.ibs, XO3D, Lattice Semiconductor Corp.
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|   Model lvc330f080haaaaaaaio
[Model] lvc330f080haaaaaaaio
Model_type I/O
Polarity   Non-Inverting
Enable   Active-Low
Vinl =  0.800V
Vinh =  2.000V
Vmeas =  1.650V
Cref =  0.0F
Rref =  1.000M
Vref =  0.0V
C_comp   4.200pF   3.800pF   7.500pF
[Temperature Range]   25.000   0.105k   -40.000
[Voltage Range]   3.300V   3.140V   3.470V
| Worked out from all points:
|   slope of the pulldown table from 0 to 0.495 V, typ, clamps not added: 24.3 ohm
|   slope of the pullup table from 0 to 0.495 V, typ, clamps not added: 26.7 ohm
|   GND clamp passes 1 mA (typ) near -0.43 V on its own axis
|   POWER clamp passes 1 mA (typ) near -0.53 V on its own axis
|   rising waveform, R_fixture 50.000, V_fixture 0.0: 20-80 % time 244ps typ, 324ps min, 148ps max; typ from 0 V to 1.96 V
|   rising waveform, R_fixture 50.000, V_fixture 3.300: 20-80 % time 155ps typ, 230ps min, 93.4ps max; typ from 1.27 V to 3.3 V
|   falling waveform, R_fixture 50.000, V_fixture 3.300: 20-80 % time 268ps typ, 327ps min, 189ps max; typ from 3.3 V to 1.27 V
|   falling waveform, R_fixture 50.000, V_fixture 0.0: 20-80 % time 136ps typ, 199ps min, 93.9ps max; typ from 1.96 V to 0 V
[Pulldown]
|Voltage   I(typ)   I(min)   I(max)
-3.3V     -29.32mA   -17.9mA    -45.21mA
-900mV    -29.32mA   -17.9mA    -45.21mA
-500mV    -22.04mA   -15.61mA   -31.59mA
600mV     23.9mA     16.31mA    35.23mA
1.2V      38.8mA     26.54mA    56.81mA
1.9V      44.78mA    31.02mA    64.46mA
4V        49.1mA     35.45mA    69.72mA
4.5V      56.03mA    41.15mA    76.83mA
5.1V      72.91mA    53.22mA    102.5mA
5.6V      95.22mA    68.23mA    138.3mA
6.1V      125.6mA    88.09mA    187.6mA
6.6V      163.8mA    112.3mA    249.8mA
[Pullup]
|Voltage   I(typ)   I(min)   I(max)
-3.3V     153.9mA    111.7mA    243.6mA
-2.7V     123.6mA    91.02mA    200.3mA
-2.1V     94.5mA     70.65mA    150.5mA
-1.6V     71.34mA    53.9mA     111.6mA
-700mV    31.42mA    23.96mA    46.76mA
300mV     -11.82mA   -8.831mA   -18.38mA
700mV     -24.77mA   -18.36mA   -38.83mA
1.1V      -34.65mA   -25.44mA   -54.83mA
1.7V      -44.02mA   -31.73mA   -70.96mA
2.3V      -47.65mA   -33.78mA   -78.43mA
4.5V      -52.35mA   -36.84mA   -87.07mA
6.6V      -55.19mA   -38.7mA    -92.41mA
[GND_clamp]
|Voltage   I(typ)   I(min)   I(max)
-3.3V     -4.507A    -3.482A    -6.263A
-1.089V   -398.4mA   -420.6mA   -374.7mA
-1.022V   -290.7mA   -338.6mA   -230.6mA
-955mV    -191.4mA   -260.2mA   -120.1mA
-888mV    -107.5mA   -187mA     -73.7mA
-821mV    -53mA      -121.4mA   -59.85mA
-754mV    -31.41mA   -66.94mA   -47.47mA
-687mV    -21.17mA   -28.82mA   -34.25mA
-620mV    -13.21mA   -10.23mA   -22mA
-553mV    -6.875mA   -3.578mA   -11.73mA
-352mV    -176.3uA   -89.98uA   -279uA
3.3V      50.87nA    0A         -26.43uA
[POWER_clamp]
|Voltage   I(typ)   I(min)   I(max)
-3.3V     62.1mA     51.02mA    92.7mA
-1.926V   36.35mA    28.59mA    56.55mA
-1.591V   28.28mA    21.98mA    45.01mA
-1.189V   18.03mA    13.9mA     29.96mA
-1.122V   16.26mA    12.55mA    27.31mA
-988mV    12.68mA    9.882mA    21.88mA
-787mV    7.154mA    5.963mA    13.15mA
-653mV    3.439mA    3.462mA    6.207mA
-586mV    1.819mA    2.29mA     3.395mA
-519mV    748.7uA    1.242mA    1.434mA
-452mV    255.4uA    468.1uA    442.9uA
3.3V      0A         0A         0A
[Ramp]
| variable   typ   min   max
dV/dt_r   1.177/0.244n   0.928/0.325n   1.503/0.147n
dV/dt_f   1.215/0.273n   0.902/0.331n   1.513/0.190n
R_load = 50.000
[Rising Waveform]
R_fixture= 50.000
V_fixture= 0.0
V_fixture_min= 0.0
V_fixture_max= 0.0
|time   V(typ)   V(min)   V(max)
0s        17.57nV    44.81nV    205.1nV
561ps     41.01uV    -2.898uV   -26.41mV
733ps     143.1uV    -2.898uV   1.857V
940ps     -39.08mV   20.92uV    2.341V
1.146ns   1.185V     362.9uV    2.427V
1.345ns   1.686V     -18.39mV   2.461V
1.535ns   1.821V     28.85mV    2.481V
1.933ns   1.911V     1.236V     2.498V
2.576ns   1.946V     1.491V     2.504V
20ns      1.962V     1.547V     2.504V
[Rising Waveform]
R_fixture= 50.000
V_fixture= 3.300
V_fixture_min= 3.140
V_fixture_max= 3.470
|time   V(typ)   V(min)   V(max)
0s        1.275V     1.637V     949.1mV
517ps     1.275V     1.637V     971.8mV
559ps     1.275V     1.637V     1.292V
664ps     1.276V     1.637V     2.974V
823ps     1.278V     1.637V     3.363V
1.067ns   2.897V     1.637V     3.429V
1.323ns   3.226V     1.694V     3.452V
1.674ns   3.273V     2.942V     3.464V
2.068ns   3.29V      3.106V     3.468V
20ns      3.3V       3.14V      3.47V
[Falling Waveform]
R_fixture= 50.000
V_fixture= 3.300
V_fixture_min= 3.140
V_fixture_max= 3.470
|time   V(typ)   V(min)   V(max)
0s        3.3V       3.14V      3.47V
563ps     3.3V       3.14V      3.52V
750ps     3.3V       3.14V      1.737V
963ps     3.354V     3.14V      1.134V
1.157ns   2.174V     3.139V     1.027V
1.318ns   1.679V     3.139V     994.5mV
1.617ns   1.401V     3.179V     969.5mV
2.036ns   1.316V     1.952V     953mV
2.705ns   1.288V     1.684V     949.7mV
20ns      1.275V     1.637V     949mV
[Falling Waveform]
R_fixture= 50.000
V_fixture= 0.0
V_fixture_min= 0.0
V_fixture_max= 0.0
|time   V(typ)   V(min)   V(max)
0s        1.962V     1.547V     2.504V
539ps     1.962V     1.547V     2.483V
696ps     1.962V     1.547V     369.2mV
918ps     1.879V     1.547V     63.11mV
1.047ns   726.5mV    1.547V     36.63mV
1.177ns   184.1mV    1.546V     22.47mV
1.469ns   40.41mV    1.533V     7.796mV
1.806ns   14.91mV    220.1mV    2.101mV
2.189ns   5.255mV    30.58mV    641.8uV
20ns      -122nV     83.95nV    41.95nV
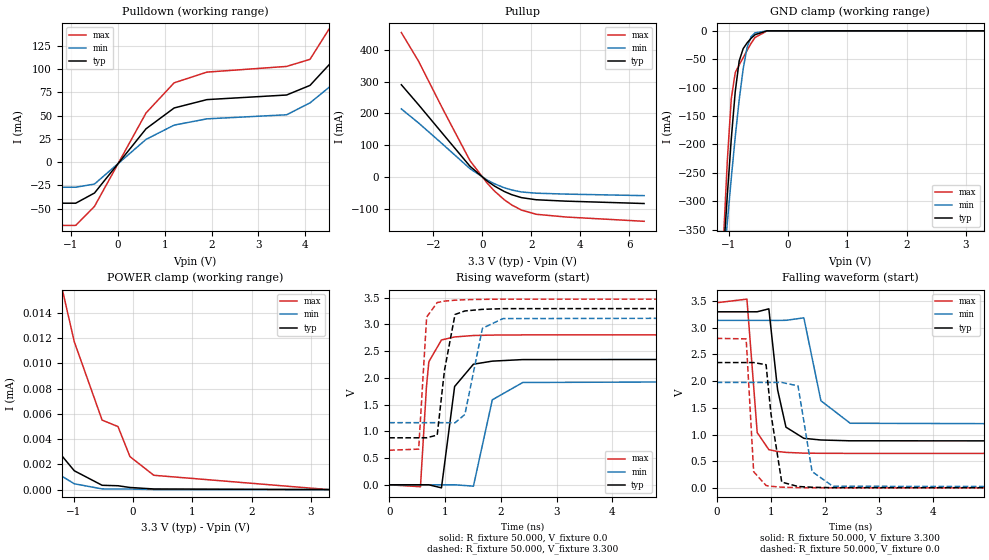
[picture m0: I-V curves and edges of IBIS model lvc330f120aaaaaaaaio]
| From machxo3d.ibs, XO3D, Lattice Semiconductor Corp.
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|   Model lvc330f120aaaaaaaaio
[Model] lvc330f120aaaaaaaaio
Model_type I/O
Polarity   Non-Inverting
Enable   Active-Low
Vinl =  0.800V
Vinh =  2.000V
Vmeas =  1.650V
Cref =  0.0F
Rref =  1.000M
Vref =  0.0V
C_comp   4.200pF   3.800pF   7.500pF
[Temperature Range]   25.000   0.105k   -40.000
[Voltage Range]   3.300V   3.140V   3.470V
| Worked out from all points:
|   slope of the pulldown table from 0 to 0.495 V, typ, clamps not added: 16.2 ohm
|   slope of the pullup table from 0 to 0.495 V, typ, clamps not added: 17.8 ohm
|   GND clamp passes 1 mA (typ) near -0.43 V on its own axis
|   rising waveform, R_fixture 50.000, V_fixture 0.0: 20-80 % time 168ps typ, 243ps min, 97.5ps max; typ from 0 V to 2.35 V
|   rising waveform, R_fixture 50.000, V_fixture 3.300: 20-80 % time 130ps typ, 209ps min, 73.1ps max; typ from 0.878 V to 3.3 V
|   falling waveform, R_fixture 50.000, V_fixture 3.300: 20-80 % time 177ps typ, 263ps min, 116ps max; typ from 3.3 V to 0.878 V
|   falling waveform, R_fixture 50.000, V_fixture 0.0: 20-80 % time 108ps typ, 168ps min, 72.2ps max; typ from 2.35 V to 0 V
[Pulldown]
|Voltage   I(typ)   I(min)   I(max)
-3.3V     -43.98mA   -26.85mA   -67.81mA
-900mV    -43.98mA   -26.85mA   -67.81mA
-500mV    -33.06mA   -23.42mA   -47.39mA
600mV     35.86mA    24.47mA    52.84mA
1.2V      58.2mA     39.81mA    85.22mA
1.9V      67.18mA    46.53mA    96.69mA
3.6V      72.12mA    50.89mA    102.8mA
4.1V      82.44mA    63.66mA    110.4mA
4.8V      120.5mA    92.38mA    166.3mA
5.4V      167.5mA    125.9mA    239.7mA
6V        229.2mA    167.9mA    338.6mA
6.6V      304.1mA    215.8mA    460.7mA
[Pullup]
|Voltage   I(typ)   I(min)   I(max)
-3.3V     290.1mA    214.2mA    453.9mA
-2.6V     227.5mA    170.3mA    364.3mA
-1.6V     135.2mA    102.5mA    212.5mA
-500mV    34.11mA    26.62mA    51.65mA
200mV     -12.13mA   -9.077mA   -18.82mA
500mV     -28.04mA   -20.86mA   -43.76mA
900mV     -45.13mA   -33.29mA   -71.06mA
1.2V      -54.99mA   -40.25mA   -87.25mA
1.6V      -64.35mA   -46.53mA   -103.4mA
2.2V      -70.98mA   -50.38mA   -116.5mA
3.4V      -75.29mA   -53.18mA   -125.1mA
6.6V      -82.78mA   -58.05mA   -138.6mA
[GND_clamp]
|Voltage   I(typ)   I(min)   I(max)
-3.3V     -4.507A    -3.482A    -6.263A
-1.089V   -398.4mA   -420.6mA   -374.7mA
-1.022V   -290.7mA   -338.6mA   -230.6mA
-955mV    -191.3mA   -260.2mA   -120mA
-888mV    -107.5mA   -187mA     -73.64mA
-821mV    -52.96mA   -121.4mA   -59.79mA
-754mV    -31.36mA   -66.92mA   -47.4mA
-687mV    -21.12mA   -28.79mA   -34.18mA
-620mV    -13.16mA   -10.19mA   -21.93mA
-553mV    -6.814mA   -3.53mA    -11.64mA
-352mV    -96.36uA   -46.21uA   -149.8uA
3.3V      0A         0A         0A
[POWER_clamp]
|Voltage   I(typ)   I(min)   I(max)
-3.3V     732.2uA    455.9uA    1.265mA
-2.663V   69.44uA    15.46uA    306.8uA
-2.529V   27.69uA    10.95uA    164.1uA
-2.328V   15.69uA    8.497uA    64.68uA
-1.725V   7.348uA    3.693uA    30.69uA
-1.189V   2.632uA    1.04uA     15.85uA
-988mV    1.494uA    463nA      11.72uA
-519mV    342.8nA    54.74nA    5.51uA
-251mV    305.1nA    47.62nA    4.994uA
-50mV     169nA      47.62nA    2.616uA
352mV     50.67nA    4.149nA    1.135uA
3.3V      0A         0A         0A
[Ramp]
| variable   typ   min   max
dV/dt_r   1.409/0.167n   1.186/0.243n   1.681/97.216p
dV/dt_f   1.453/0.177n   1.187/0.261n   1.695/0.115n
R_load = 50.000
[Rising Waveform]
R_fixture= 50.000
V_fixture= 0.0
V_fixture_min= 0.0
V_fixture_max= 0.0
|time   V(typ)   V(min)   V(max)
0s        13.28nV    34.6nV     153.1nV
560ps     39.61uV    -5.059uV   -36.45mV
667ps     245.1uV    -5.059uV   1.825V
710ps     146.3uV    -5.059uV   2.299V
936ps     -57.45mV   94.86uV    2.707V
1.172ns   1.837V     152.4uV    2.763V
1.509ns   2.254V     -25.52mV   2.79V
1.847ns   2.311V     1.588V     2.798V
2.392ns   2.34V      1.912V     2.801V
20ns      2.349V     1.976V     2.802V
[Rising Waveform]
R_fixture= 50.000
V_fixture= 3.300
V_fixture_min= 3.140
V_fixture_max= 3.470
|time   V(typ)   V(min)   V(max)
0s        878.1mV    1.161V     645.8mV
528ps     878.1mV    1.161V     666.3mV
671ps     878.8mV    1.161V     3.135V
860ps     928.9mV    1.161V     3.406V
990ps     2.137V     1.161V     3.433V
1.179ns   3.183V     1.159V     3.45V
1.356ns   3.249V     1.315V     3.459V
1.67ns    3.279V     2.925V     3.466V
2.037ns   3.292V     3.106V     3.469V
20ns      3.3V       3.14V      3.47V
[Falling Waveform]
R_fixture= 50.000
V_fixture= 3.300
V_fixture_min= 3.140
V_fixture_max= 3.470
|time   V(typ)   V(min)   V(max)
0s        3.3V       3.14V      3.47V
560ps     3.3V       3.14V      3.538V
751ps     3.301V     3.14V      1.035V
966ps     3.356V     3.14V      716.7mV
1.128ns   1.841V     3.139V     681.5mV
1.283ns   1.138V     3.141V     665mV
1.615ns   928.5mV    3.187V     650.9mV
1.931ns   897.4mV    1.633V     647.9mV
2.474ns   882mV      1.211V     646mV
20ns      878.1mV    1.161V     645.8mV
[Falling Waveform]
R_fixture= 50.000
V_fixture= 0.0
V_fixture_min= 0.0
V_fixture_max= 0.0
|time   V(typ)   V(min)   V(max)
0s        2.349V     1.976V     2.802V
546ps     2.349V     1.976V     2.793V
685ps     2.349V     1.976V     302.2mV
915ps     2.308V     1.976V     43.39mV
1.005ns   1.39V      1.976V     29.09mV
1.205ns   107.7mV    1.976V     12.64mV
1.507ns   25.72mV    1.912V     4.034mV
1.767ns   11.41mV    305.2mV    1.55mV
2.152ns   3.441mV    30.35mV    380.6uV
20ns      -8.341nV   -8.644nV   158.7nV
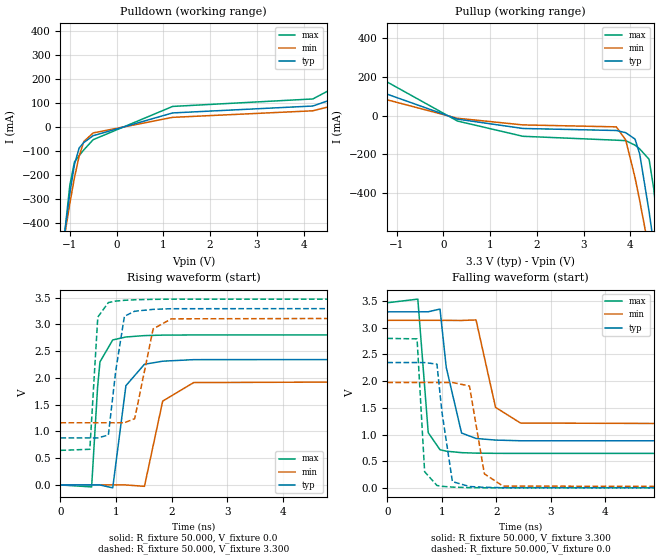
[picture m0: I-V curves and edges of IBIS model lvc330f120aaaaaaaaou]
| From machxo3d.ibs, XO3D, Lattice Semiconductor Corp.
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|   Model lvc330f120aaaaaaaaou
[Model] lvc330f120aaaaaaaaou
Model_type Output
Polarity   Non-Inverting
Enable   Active-High
Vmeas =  1.650V
Cref =  0.0F
Rref =  1.000M
Vref =  0.0V
C_comp   4.200pF   3.800pF   7.500pF
[Temperature Range]   25.000   0.105k   -40.000
[Voltage Range]   3.300V   3.140V   3.470V
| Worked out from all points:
|   slope of the pulldown table from 0 to 0.495 V, typ, clamps not added: 16.2 ohm
|   slope of the pullup table from 0 to 0.495 V, typ, clamps not added: 17.8 ohm
|   rising waveform, R_fixture 50.000, V_fixture 0.0: 20-80 % time 168ps typ, 244ps min, 97.5ps max; typ from 0 V to 2.35 V
|   rising waveform, R_fixture 50.000, V_fixture 3.300: 20-80 % time 130ps typ, 209ps min, 73.1ps max; typ from 0.878 V to 3.3 V
|   falling waveform, R_fixture 50.000, V_fixture 3.300: 20-80 % time 178ps typ, 262ps min, 116ps max; typ from 3.3 V to 0.878 V
|   falling waveform, R_fixture 50.000, V_fixture 0.0: 20-80 % time 108ps typ, 167ps min, 72.2ps max; typ from 2.35 V to 0 V
[Pulldown]
|Voltage   I(typ)   I(min)   I(max)
-3.3V     -4.507A    -3.483A    -6.263A
-1.1V     -426.7mA   -439.1mA   -425mA
-1V       -276.1mA   -319.1mA   -243.2mA
-900mV    -156.2mA   -210.3mA   -145.7mA
-800mV    -87.54mA   -121.3mA   -119.5mA
-700mV    -64.61mA   -60.71mA   -95.41mA
-500mV    -36.31mA   -24.81mA   -52.97mA
1.2V      58.2mA     39.81mA    85.22mA
4.2V      86.92mA    67.08mA    116.3mA
5.4V      167.5mA    126mA      239.8mA
6.4V      278.4mA    199.8mA    418.6mA
6.6V      304.8mA    216.4mA    461.6mA
[Pullup]
|Voltage   I(typ)   I(min)   I(max)
-3.3V     290.8mA    214.7mA    455.2mA
300mV     -17.73mA   -13.25mA   -27.57mA
1.7V      -66.04mA   -47.59mA   -106.4mA
3.7V      -76.51mA   -57.72mA   -126.6mA
3.9V      -87.81mA   -125.4mA   -128.9mA
4.1V      -120.9mA   -320.5mA   -152.3mA
4.2V      -198.5mA   -439.5mA   -171.8mA
4.4V      -494.9mA   -694.9mA   -225.2mA
4.5V      -665.4mA   -827.4mA   -377.2mA
4.6V      -841.6mA   -961.9mA   -601.4mA
4.7V      -1.021A    -1.098A    -846.9mA
6.6V      -4.589A    -3.768A    -5.939A
[Ramp]
| variable   typ   min   max
dV/dt_r   1.409/0.167n   1.186/0.243n   1.681/97.202p
dV/dt_f   1.453/0.177n   1.187/0.261n   1.695/0.115n
R_load = 50.000
[Rising Waveform]
R_fixture= 50.000
V_fixture= 0.0
V_fixture_min= 0.0
V_fixture_max= 0.0
|time   V(typ)   V(min)   V(max)
0s        13.28nV    34.6nV     153.1nV
560ps     37.72uV    -6.822uV   -36.44mV
667ps     236.3uV    -6.822uV   1.825V
710ps     142.6uV    -6.822uV   2.299V
939ps     -54.11mV   79.27uV    2.708V
1.176ns   1.854V     149.3uV    2.763V
1.509ns   2.254V     -25.52mV   2.789V
1.837ns   2.311V     1.566V     2.798V
2.393ns   2.34V      1.912V     2.801V
20ns      2.349V     1.976V     2.802V
[Rising Waveform]
R_fixture= 50.000
V_fixture= 3.300
V_fixture_min= 3.140
V_fixture_max= 3.470
|time   V(typ)   V(min)   V(max)
0s        878.1mV    1.161V     645.8mV
528ps     878.1mV    1.161V     666.4mV
671ps     878.8mV    1.161V     3.135V
861ps     932.2mV    1.161V     3.406V
994ps     2.137V     1.161V     3.433V
1.149ns   3.15V      1.162V     3.448V
1.334ns   3.244V     1.238V     3.458V
1.665ns   3.279V     2.914V     3.466V
1.992ns   3.291V     3.102V     3.469V
20ns      3.3V       3.14V      3.47V
[Falling Waveform]
R_fixture= 50.000
V_fixture= 3.300
V_fixture_min= 3.140
V_fixture_max= 3.470
|time   V(typ)   V(min)   V(max)
0s        3.3V       3.14V      3.47V
560ps     3.3V       3.14V      3.538V
751ps     3.301V     3.14V      1.035V
967ps     3.352V     3.14V      715mV
1.082ns   2.258V     3.14V      687.8mV
1.363ns   1.028V     3.138V     659.9mV
1.629ns   925.8mV    3.148V     650.9mV
1.987ns   895.9mV    1.509V     647.1mV
2.446ns   882.9mV    1.215V     646mV
20ns      878mV      1.161V     645.8mV
[Falling Waveform]
R_fixture= 50.000
V_fixture= 0.0
V_fixture_min= 0.0
V_fixture_max= 0.0
|time   V(typ)   V(min)   V(max)
0s        2.349V     1.976V     2.802V
546ps     2.349V     1.976V     2.793V
685ps     2.349V     1.976V     302.2mV
911ps     2.319V     1.976V     44.73mV
1.003ns   1.421V     1.976V     29.2mV
1.195ns   117.1mV    1.976V     14.08mV
1.508ns   25.23mV    1.909V     3.965mV
1.782ns   10.85mV    262.9mV    1.525mV
2.124ns   3.838mV    33.19mV    505.5uV
20ns      -7.464nV   -27.45nV   89.81nV
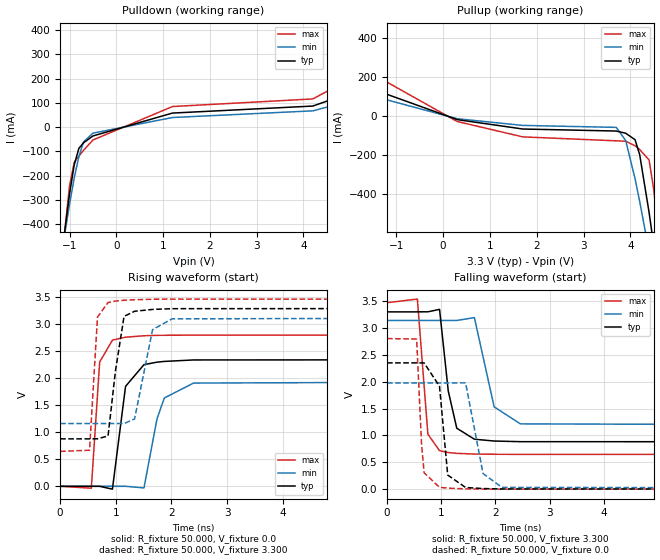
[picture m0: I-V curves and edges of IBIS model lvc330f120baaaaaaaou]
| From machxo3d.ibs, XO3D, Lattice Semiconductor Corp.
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|   Model lvc330f120baaaaaaaou
[Model] lvc330f120baaaaaaaou
Model_type Output
Polarity   Non-Inverting
Enable   Active-High
Vmeas =  1.650V
Cref =  0.0F
Rref =  1.000M
Vref =  0.0V
C_comp   4.200pF   3.800pF   7.500pF
[Temperature Range]   25.000   0.105k   -40.000
[Voltage Range]   3.300V   3.140V   3.470V
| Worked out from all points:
|   slope of the pulldown table from 0 to 0.495 V, typ, clamps not added: 16.2 ohm
|   slope of the pullup table from 0 to 0.495 V, typ, clamps not added: 17.8 ohm
|   rising waveform, R_fixture 50.000, V_fixture 0.0: 20-80 % time 168ps typ, 246ps min, 97.3ps max; typ from 0.002 V to 2.35 V
|   rising waveform, R_fixture 50.000, V_fixture 3.300: 20-80 % time 130ps typ, 209ps min, 73ps max; typ from 0.88 V to 3.3 V
|   falling waveform, R_fixture 50.000, V_fixture 3.300: 20-80 % time 178ps typ, 263ps min, 116ps max; typ from 3.3 V to 0.88 V
|   falling waveform, R_fixture 50.000, V_fixture 0.0: 20-80 % time 108ps typ, 168ps min, 72.3ps max; typ from 2.35 V to 0.002 V
[Pulldown]
|Voltage   I(typ)   I(min)   I(max)
-3.3V     -4.507A    -3.483A    -6.263A
-1.1V     -426.7mA   -439.1mA   -425.1mA
-1V       -276.1mA   -319.1mA   -243.3mA
-900mV    -156.3mA   -210.4mA   -145.7mA
-800mV    -87.59mA   -121.4mA   -119.6mA
-700mV    -64.68mA   -60.75mA   -95.51mA
-500mV    -36.41mA   -24.89mA   -53.12mA
1.2V      58.06mA    39.72mA    84.98mA
4.2V      87.02mA    67.25mA    116.4mA
5.4V      168.3mA    127.4mA    240.2mA
6.4V      280.9mA    203.8mA    420.6mA
6.6V      307.8mA    221.2mA    464.2mA
[Pullup]
|Voltage   I(typ)   I(min)   I(max)
-3.3V     294.1mA    218.9mA    458.3mA
300mV     -17.76mA   -13.27mA   -27.62mA
1.7V      -66.16mA   -47.67mA   -106.6mA
3.7V      -76.63mA   -57.78mA   -126.9mA
3.9V      -87.87mA   -125.4mA   -129.1mA
4.1V      -120.9mA   -320.5mA   -152.3mA
4.2V      -198.5mA   -439.5mA   -171.8mA
4.4V      -494.9mA   -694.9mA   -225.3mA
4.5V      -665.5mA   -827.4mA   -377.3mA
4.6V      -841.6mA   -961.9mA   -601.4mA
4.7V      -1.021A    -1.098A    -846.9mA
6.6V      -4.589A    -3.768A    -5.939A
[Ramp]
| variable   typ   min   max
dV/dt_r   1.409/0.167n   1.186/0.243n   1.681/96.968p
dV/dt_f   1.452/0.178n   1.186/0.262n   1.693/0.115n
R_load = 50.000
[Rising Waveform]
R_fixture= 50.000
V_fixture= 0.0
V_fixture_min= 0.0
V_fixture_max= 0.0
|time   V(typ)   V(min)   V(max)
0s        1.574mV    1.318mV    1.97mV
560ps     1.611mV    1.31mV     -33.88mV
710ps     1.708mV    1.31mV     2.303V
939ps     -51.61mV   1.435mV    2.709V
1.175ns   1.853V     1.459mV    2.764V
1.506ns   2.255V     -28.25mV   2.79V
1.739ns   2.301V     1.246V     2.798V
1.871ns   2.315V     1.637V     2.799V
2.396ns   2.342V     1.914V     2.802V
20ns      2.351V     1.978V     2.803V
[Rising Waveform]
R_fixture= 50.000
V_fixture= 3.300
V_fixture_min= 3.140
V_fixture_max= 3.470
|time   V(typ)   V(min)   V(max)
0s        880.5mV    1.164V     648.5mV
528ps     880.5mV    1.164V     669.6mV
671ps     881.2mV    1.164V     3.137V
861ps     935mV      1.164V     3.407V
994ps     2.141V     1.164V     3.433V
1.148ns   3.149V     1.164V     3.449V
1.337ns   3.244V     1.249V     3.458V
1.66ns    3.278V     2.903V     3.466V
2.01ns    3.292V     3.104V     3.469V
20ns      3.3V       3.14V      3.47V
[Falling Waveform]
R_fixture= 50.000
V_fixture= 3.300
V_fixture_min= 3.140
V_fixture_max= 3.470
|time   V(typ)   V(min)   V(max)
0s        3.3V       3.14V      3.47V
560ps     3.3V       3.14V      3.538V
754ps     3.301V     3.14V      1.024V
969ps     3.346V     3.14V      717.6mV
1.13ns    1.828V     3.14V      683.3mV
1.287ns   1.135V     3.14V      667.5mV
1.612ns   930.6mV    3.193V     654.6mV
1.977ns   896.9mV    1.532V     650.5mV
2.461ns   884.8mV    1.216V     648.8mV
20ns      880.4mV    1.163V     648.5mV
[Falling Waveform]
R_fixture= 50.000
V_fixture= 0.0
V_fixture_min= 0.0
V_fixture_max= 0.0
|time   V(typ)   V(min)   V(max)
0s        2.351V     1.978V     2.803V
546ps     2.351V     1.978V     2.794V
637ps     2.35V      1.978V     839.3mV
685ps     2.35V      1.978V     305.6mV
968ps     1.917V     1.978V     36.04mV
1.12ns    263.6mV    1.978V     20.51mV
1.45ns    32.37mV    1.979V     6.836mV
1.772ns   12.61mV    292.9mV    3.473mV
2.118ns   5.515mV    35.34mV    2.461mV
20ns      1.574mV    1.317mV    1.97mV
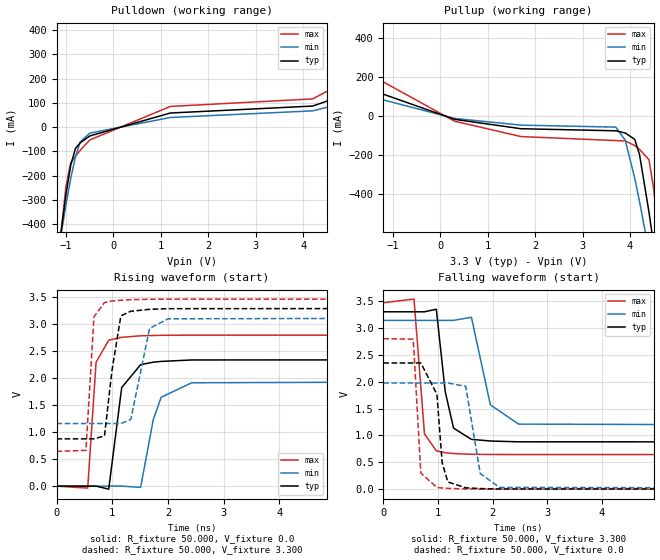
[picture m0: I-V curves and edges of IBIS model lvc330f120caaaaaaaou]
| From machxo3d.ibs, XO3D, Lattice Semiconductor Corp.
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|   Model lvc330f120caaaaaaaou
[Model] lvc330f120caaaaaaaou
Model_type Output
Polarity   Non-Inverting
Enable   Active-High
Vmeas =  1.650V
Cref =  0.0F
Rref =  1.000M
Vref =  0.0V
C_comp   4.200pF   3.800pF   7.500pF
[Temperature Range]   25.000   0.105k   -40.000
[Voltage Range]   3.300V   3.140V   3.470V
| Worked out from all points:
|   slope of the pulldown table from 0 to 0.495 V, typ, clamps not added: 16.2 ohm
|   slope of the pullup table from 0 to 0.495 V, typ, clamps not added: 17.8 ohm
|   rising waveform, R_fixture 50.000, V_fixture 0.0: 20-80 % time 169ps typ, 244ps min, 97.5ps max; typ from 0 V to 2.35 V
|   rising waveform, R_fixture 50.000, V_fixture 3.300: 20-80 % time 129ps typ, 210ps min, 73.1ps max; typ from 0.876 V to 3.3 V
|   falling waveform, R_fixture 50.000, V_fixture 3.300: 20-80 % time 177ps typ, 261ps min, 115ps max; typ from 3.3 V to 0.876 V
|   falling waveform, R_fixture 50.000, V_fixture 0.0: 20-80 % time 108ps typ, 168ps min, 71.9ps max; typ from 2.35 V to 0 V
[Pulldown]
|Voltage   I(typ)   I(min)   I(max)
-3.3V     -4.507A    -3.483A    -6.263A
-1.1V     -426.7mA   -439.1mA   -425mA
-1V       -276.1mA   -319.1mA   -243.3mA
-900mV    -156.3mA   -210.4mA   -145.7mA
-800mV    -87.58mA   -121.4mA   -119.6mA
-700mV    -64.66mA   -60.74mA   -95.48mA
-500mV    -36.38mA   -24.87mA   -53.08mA
1.2V      58.29mA    39.84mA    85.45mA
4.2V      87.01mA    67.13mA    116.5mA
5.4V      167.6mA    126mA      240mA
6.4V      278.6mA    199.9mA    418.9mA
6.6V      305mA      216.5mA    462.1mA
[Pullup]
|Voltage   I(typ)   I(min)   I(max)
-3.3V     291.1mA    214.8mA    455.7mA
300mV     -17.63mA   -13.21mA   -27.32mA
1.7V      -65.94mA   -47.55mA   -106.2mA
3.7V      -76.59mA   -57.76mA   -126.7mA
3.9V      -87.85mA   -125.4mA   -129mA
4.1V      -120.9mA   -320.5mA   -152.3mA
4.2V      -198.5mA   -439.5mA   -171.8mA
4.4V      -494.9mA   -694.9mA   -225.3mA
4.5V      -665.5mA   -827.4mA   -377.2mA
4.6V      -841.6mA   -961.9mA   -601.4mA
4.7V      -1.021A    -1.098A    -846.9mA
6.6V      -4.589A    -3.768A    -5.939A
[Ramp]
| variable   typ   min   max
dV/dt_r   1.408/0.167n   1.185/0.243n   1.680/97.205p
dV/dt_f   1.453/0.177n   1.188/0.261n   1.695/0.115n
R_load = 50.000
[Rising Waveform]
R_fixture= 50.000
V_fixture= 0.0
V_fixture_min= 0.0
V_fixture_max= 0.0
|time   V(typ)   V(min)   V(max)
0s        13.01nV    34.25nV    147.9nV
560ps     37.66uV    -6.837uV   -36.36mV
710ps     139.9uV    -6.837uV   2.297V
937ps     -56.38mV   79.23uV    2.705V
1.17ns    1.827V     147.6uV    2.759V
1.51ns    2.252V     -23.59mV   2.787V
1.737ns   2.298V     1.233V     2.793V
1.879ns   2.312V     1.648V     2.796V
2.427ns   2.339V     1.916V     2.799V
20ns      2.347V     1.975V     2.799V
[Rising Waveform]
R_fixture= 50.000
V_fixture= 3.300
V_fixture_min= 3.140
V_fixture_max= 3.470
|time   V(typ)   V(min)   V(max)
0s        876.5mV    1.16V      643.5mV
528ps     876.5mV    1.16V      663.6mV
672ps     877.1mV    1.16V      3.138V
861ps     930.3mV    1.16V      3.404V
994ps     2.134V     1.16V      3.431V
1.155ns   3.156V     1.16V      3.446V
1.334ns   3.242V     1.237V     3.457V
1.67ns    3.278V     2.924V     3.464V
2.004ns   3.29V      3.102V     3.466V
20ns      3.299V     3.139V     3.468V
[Falling Waveform]
R_fixture= 50.000
V_fixture= 3.300
V_fixture_min= 3.140
V_fixture_max= 3.470
|time   V(typ)   V(min)   V(max)
0s        3.299V     3.139V     3.468V
560ps     3.299V     3.139V     3.536V
751ps     3.299V     3.139V     1.03V
968ps     3.347V     3.139V     713.2mV
1.131ns   1.814V     3.139V     677.8mV
1.283ns   1.136V     3.14V      662.5mV
1.61ns    926.4mV    3.197V     649.1mV
1.957ns   895.8mV    1.569V     645.5mV
2.473ns   880.7mV    1.21V      643.7mV
20ns      876.4mV    1.16V      643.5mV
[Falling Waveform]
R_fixture= 50.000
V_fixture= 0.0
V_fixture_min= 0.0
V_fixture_max= 0.0
|time   V(typ)   V(min)   V(max)
0s        2.347V     1.975V     2.799V
546ps     2.347V     1.975V     2.79V
685ps     2.347V     1.975V     299.1mV
979ps     1.765V     1.975V     31.77mV
1.075ns   490.3mV    1.975V     21.39mV
1.179ns   134.1mV    1.975V     14.77mV
1.506ns   25.21mV    1.913V     3.953mV
1.772ns   10.9mV     289.4mV    1.515mV
2.126ns   3.834mV    32.74mV    497.1uV
20ns      -175.6nV   133.7nV    13.89nV
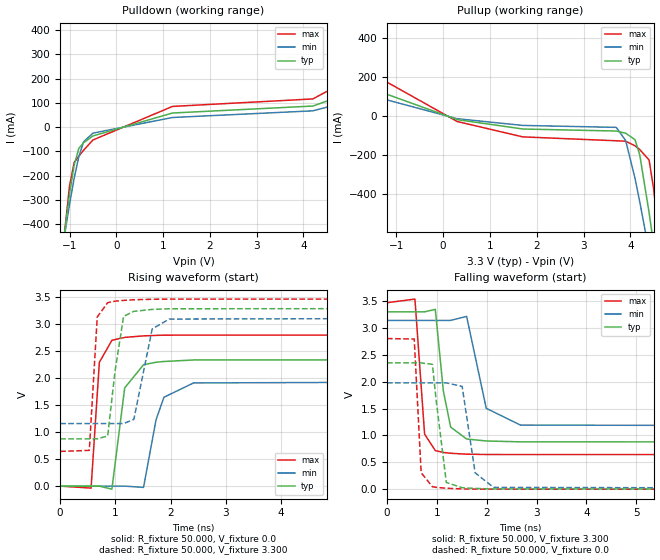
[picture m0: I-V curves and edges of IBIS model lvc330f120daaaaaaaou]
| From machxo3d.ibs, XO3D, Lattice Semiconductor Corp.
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|   Model lvc330f120daaaaaaaou
[Model] lvc330f120daaaaaaaou
Model_type Output
Polarity   Non-Inverting
Enable   Active-High
Vmeas =  1.650V
Cref =  0.0F
Rref =  1.000M
Vref =  0.0V
C_comp   4.200pF   3.800pF   7.500pF
[Temperature Range]   25.000   0.105k   -40.000
[Voltage Range]   3.300V   3.140V   3.470V
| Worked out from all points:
|   slope of the pulldown table from 0 to 0.495 V, typ, clamps not added: 16.2 ohm
|   slope of the pullup table from 0 to 0.495 V, typ, clamps not added: 17.8 ohm
|   rising waveform, R_fixture 50.000, V_fixture 0.0: 20-80 % time 169ps typ, 245ps min, 97.9ps max; typ from 0 V to 2.35 V
|   rising waveform, R_fixture 50.000, V_fixture 3.300: 20-80 % time 130ps typ, 210ps min, 73.3ps max; typ from 0.876 V to 3.3 V
|   falling waveform, R_fixture 50.000, V_fixture 3.300: 20-80 % time 178ps typ, 263ps min, 116ps max; typ from 3.3 V to 0.876 V
|   falling waveform, R_fixture 50.000, V_fixture 0.0: 20-80 % time 108ps typ, 168ps min, 72.4ps max; typ from 2.35 V to 0 V
[Pulldown]
|Voltage   I(typ)   I(min)   I(max)
-3.3V     -4.507A    -3.483A    -6.263A
-1.1V     -426.7mA   -439.1mA   -425mA
-1V       -276.1mA   -319.1mA   -243.3mA
-900mV    -156.3mA   -210.4mA   -145.7mA
-800mV    -87.58mA   -121.4mA   -119.6mA
-700mV    -64.66mA   -60.74mA   -95.48mA
-500mV    -36.38mA   -24.87mA   -53.08mA
1.2V      58.29mA    39.84mA    85.45mA
4.2V      87.02mA    67.25mA    116.4mA
5.4V      168.3mA    127.4mA    240.2mA
6.4V      280.9mA    203.8mA    420.6mA
6.6V      307.8mA    221.2mA    464.2mA
[Pullup]
|Voltage   I(typ)   I(min)   I(max)
-3.3V     294.1mA    218.9mA    458.3mA
300mV     -17.76mA   -13.27mA   -27.62mA
1.7V      -66.16mA   -47.67mA   -106.6mA
3.7V      -76.59mA   -57.76mA   -126.7mA
3.9V      -87.85mA   -125.4mA   -129mA
4.1V      -120.9mA   -320.5mA   -152.3mA
4.2V      -198.5mA   -439.5mA   -171.8mA
4.4V      -494.9mA   -694.9mA   -225.3mA
4.5V      -665.5mA   -827.4mA   -377.2mA
4.6V      -841.6mA   -961.9mA   -601.4mA
4.7V      -1.021A    -1.098A    -846.9mA
6.6V      -4.589A    -3.768A    -5.939A
[Ramp]
| variable   typ   min   max
dV/dt_r   1.410/0.168n   1.187/0.244n   1.682/97.549p
dV/dt_f   1.454/0.178n   1.188/0.263n   1.696/0.116n
R_load = 50.000
[Rising Waveform]
R_fixture= 50.000
V_fixture= 0.0
V_fixture_min= 0.0
V_fixture_max= 0.0
|time   V(typ)   V(min)   V(max)
0s        13.01nV    34.25nV    147.9nV
560ps     37.66uV    -6.854uV   -36.36mV
710ps     139.9uV    -6.854uV   2.297V
937ps     -56.38mV   79.23uV    2.705V
1.169ns   1.822V     147.6uV    2.759V
1.51ns    2.252V     -23.59mV   2.787V
1.737ns   2.298V     1.233V     2.796V
1.879ns   2.312V     1.648V     2.8V
2.415ns   2.34V      1.914V     2.802V
20ns      2.351V     1.978V     2.803V
[Rising Waveform]
R_fixture= 50.000
V_fixture= 3.300
V_fixture_min= 3.140
V_fixture_max= 3.470
|time   V(typ)   V(min)   V(max)
0s        876.5mV    1.16V      643.5mV
528ps     876.5mV    1.16V      663.6mV
672ps     877.1mV    1.16V      3.138V
861ps     930.3mV    1.16V      3.404V
994ps     2.134V     1.16V      3.431V
1.149ns   3.149V     1.161V     3.445V
1.334ns   3.242V     1.237V     3.457V
1.667ns   3.278V     2.917V     3.466V
1.976ns   3.29V      3.099V     3.469V
20ns      3.3V       3.14V      3.47V
[Falling Waveform]
R_fixture= 50.000
V_fixture= 3.300
V_fixture_min= 3.140
V_fixture_max= 3.470
|time   V(typ)   V(min)   V(max)
0s        3.3V       3.14V      3.47V
560ps     3.3V       3.14V      3.538V
754ps     3.301V     3.14V      1.024V
969ps     3.346V     3.14V      717.6mV
1.13ns    1.828V     3.14V      683.3mV
1.277ns   1.155V     3.141V     668.3mV
1.597ns   933.3mV    3.215V     651mV
1.991ns   896.9mV    1.505V     645.2mV
2.676ns   880.6mV    1.193V     643.7mV
20ns      876.4mV    1.16V      643.4mV
[Falling Waveform]
R_fixture= 50.000
V_fixture= 0.0
V_fixture_min= 0.0
V_fixture_max= 0.0
|time   V(typ)   V(min)   V(max)
0s        2.351V     1.978V     2.803V
546ps     2.351V     1.978V     2.794V
685ps     2.35V      1.978V     305.6mV
910ps     2.323V     1.978V     47.04mV
988ps     1.64V      1.978V     33.21mV
1.19ns    124.9mV    1.978V     17.23mV
1.507ns   27.35mV    1.913V     4.503mV
1.768ns   13.45mV    304.9mV    1.631mV
2.136ns   4.539mV    33.24mV    423.7uV
20ns      46.07nV    156.3nV    86.83nV
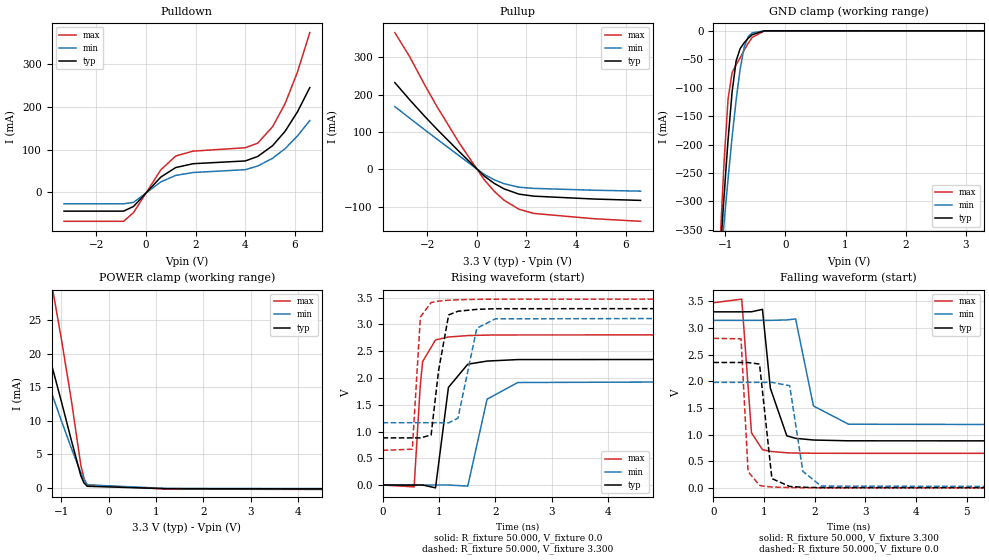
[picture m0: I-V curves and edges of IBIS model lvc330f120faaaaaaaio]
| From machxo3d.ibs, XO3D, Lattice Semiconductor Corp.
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|   Model lvc330f120faaaaaaaio
[Model] lvc330f120faaaaaaaio
Model_type I/O
Polarity   Non-Inverting
Enable   Active-Low
Vinl =  0.800V
Vinh =  2.000V
Vmeas =  1.650V
Cref =  0.0F
Rref =  1.000M
Vref =  0.0V
C_comp   4.200pF   3.800pF   7.500pF
[Temperature Range]   25.000   0.105k   -40.000
[Voltage Range]   3.300V   3.140V   3.470V
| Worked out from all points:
|   slope of the pulldown table from 0 to 0.495 V, typ, clamps not added: 16.2 ohm
|   slope of the pullup table from 0 to 0.495 V, typ, clamps not added: 17.8 ohm
|   GND clamp passes 1 mA (typ) near -0.43 V on its own axis
|   POWER clamp passes 1 mA (typ) near -0.53 V on its own axis
|   rising waveform, R_fixture 50.000, V_fixture 0.0: 20-80 % time 168ps typ, 244ps min, 97.3ps max; typ from 0.002 V to 2.35 V
|   rising waveform, R_fixture 50.000, V_fixture 3.300: 20-80 % time 130ps typ, 209ps min, 73ps max; typ from 0.88 V to 3.3 V
|   falling waveform, R_fixture 50.000, V_fixture 3.300: 20-80 % time 178ps typ, 263ps min, 116ps max; typ from 3.3 V to 0.88 V
|   falling waveform, R_fixture 50.000, V_fixture 0.0: 20-80 % time 108ps typ, 168ps min, 72.3ps max; typ from 2.35 V to 0.002 V
[Pulldown]
|Voltage   I(typ)   I(min)   I(max)
-3.3V     -43.98mA   -26.85mA   -67.81mA
-900mV    -43.98mA   -26.85mA   -67.81mA
-500mV    -33.06mA   -23.42mA   -47.39mA
600mV     35.86mA    24.47mA    52.84mA
1.2V      58.2mA     39.81mA    85.22mA
1.9V      67.18mA    46.53mA    96.69mA
4V        73.65mA    53.18mA    104.6mA
4.5V      84.05mA    61.72mA    115.2mA
5.1V      109.4mA    79.84mA    153.8mA
5.6V      142.8mA    102.3mA    207.4mA
6.1V      188.4mA    132.1mA    281.4mA
6.6V      245.6mA    168.3mA    374.6mA
[Pullup]
|Voltage   I(typ)   I(min)   I(max)
-3.3V     231.9mA    167.8mA    365.5mA
-2.7V     185.9mA    136.7mA    300.8mA
-2.1V     142mA      106.1mA    226.2mA
-1.6V     107.1mA    80.87mA    167.6mA
-700mV    47.13mA    35.94mA    70.14mA
300mV     -17.73mA   -13.25mA   -27.57mA
700mV     -37.16mA   -27.54mA   -58.24mA
1.1V      -51.98mA   -38.15mA   -82.25mA
1.7V      -66.04mA   -47.59mA   -106.4mA
2.3V      -71.47mA   -50.68mA   -117.6mA
4.7V      -79.05mA   -55.57mA   -131.6mA
6.6V      -82.78mA   -58.05mA   -138.6mA
[GND_clamp]
|Voltage   I(typ)   I(min)   I(max)
-3.3V     -4.506A    -3.482A    -6.262A
-1.089V   -398.3mA   -420.5mA   -374.5mA
-1.022V   -290.6mA   -338.5mA   -230.4mA
-955mV    -191.2mA   -260.1mA   -119.8mA
-888mV    -107.4mA   -186.9mA   -73.47mA
-821mV    -52.87mA   -121.3mA   -59.62mA
-754mV    -31.28mA   -66.86mA   -47.24mA
-687mV    -21.04mA   -28.74mA   -34.02mA
-620mV    -13.09mA   -10.15mA   -21.79mA
-553mV    -6.755mA   -3.505mA   -11.52mA
-352mV    -90.18uA   -45.39uA   -119.9uA
3.3V      0A         0A         0A
[POWER_clamp]
|Voltage   I(typ)   I(min)   I(max)
-3.3V     62.1mA     51.02mA    92.7mA
-1.926V   36.35mA    28.59mA    56.55mA
-1.591V   28.28mA    21.98mA    45.01mA
-1.189V   18.03mA    13.9mA     29.96mA
-1.122V   16.26mA    12.55mA    27.31mA
-988mV    12.68mA    9.882mA    21.88mA
-787mV    7.154mA    5.963mA    13.15mA
-586mV    1.819mA    2.29mA     3.395mA
-519mV    748.7uA    1.242mA    1.434mA
-452mV    255.4uA    468.1uA    442.9uA
1.223V    -104.1uA   -69.89uA   -164.8uA
6.6V      -145.9uA   -91.75uA   -251.2uA
[Ramp]
| variable   typ   min   max
dV/dt_r   1.409/0.167n   1.186/0.243n   1.681/96.982p
dV/dt_f   1.452/0.178n   1.186/0.262n   1.693/0.115n
R_load = 50.000
[Rising Waveform]
R_fixture= 50.000
V_fixture= 0.0
V_fixture_min= 0.0
V_fixture_max= 0.0
|time   V(typ)   V(min)   V(max)
0s        1.574mV    1.318mV    1.97mV
560ps     1.614mV    1.312mV    -33.89mV
667ps     1.817mV    1.312mV    1.831V
710ps     1.711mV    1.312mV    2.303V
939ps     -51.62mV   1.436mV    2.709V
1.168ns   1.823V     1.461mV    2.763V
1.511ns   2.256V     -19.23mV   2.79V
1.853ns   2.314V     1.603V     2.799V
2.396ns   2.342V     1.914V     2.802V
20ns      2.351V     1.978V     2.803V
[Rising Waveform]
R_fixture= 50.000
V_fixture= 3.300
V_fixture_min= 3.140
V_fixture_max= 3.470
|time   V(typ)   V(min)   V(max)
0s        880.5mV    1.164V     648.5mV
528ps     880.5mV    1.164V     669.5mV
671ps     881.1mV    1.164V     3.137V
861ps     935mV      1.164V     3.406V
994ps     2.141V     1.164V     3.433V
1.172ns   3.176V     1.162V     3.45V
1.337ns   3.244V     1.249V     3.458V
1.671ns   3.279V     2.927V     3.466V
1.999ns   3.291V     3.102V     3.469V
20ns      3.3V       3.14V      3.47V
[Falling Waveform]
R_fixture= 50.000
V_fixture= 3.300
V_fixture_min= 3.140
V_fixture_max= 3.470
|time   V(typ)   V(min)   V(max)
0s        3.3V       3.14V      3.47V
560ps     3.3V       3.14V      3.538V
752ps     3.301V     3.14V      1.034V
969ps     3.346V     3.14V      717.6mV
1.125ns   1.867V     3.14V      684.7mV
1.449ns   976.3mV    3.148V     658.7mV
1.623ns   929.9mV    3.167V     653.6mV
1.975ns   897.8mV    1.536V     649.9mV
2.668ns   882.9mV    1.194V     648.7mV
20ns      880.4mV    1.163V     648.5mV
[Falling Waveform]
R_fixture= 50.000
V_fixture= 0.0
V_fixture_min= 0.0
V_fixture_max= 0.0
|time   V(typ)   V(min)   V(max)
0s        2.351V     1.978V     2.803V
546ps     2.351V     1.978V     2.794V
685ps     2.35V      1.978V     305.6mV
911ps     2.321V     1.978V     47.27mV
987ps     1.655V     1.978V     33.63mV
1.155ns   175.2mV    1.978V     17.51mV
1.506ns   27.45mV    1.916V     5.93mV
1.766ns   12.73mV    311mV      3.475mV
2.127ns   5.305mV    34.31mV    2.458mV
20ns      1.574mV    1.317mV    1.969mV
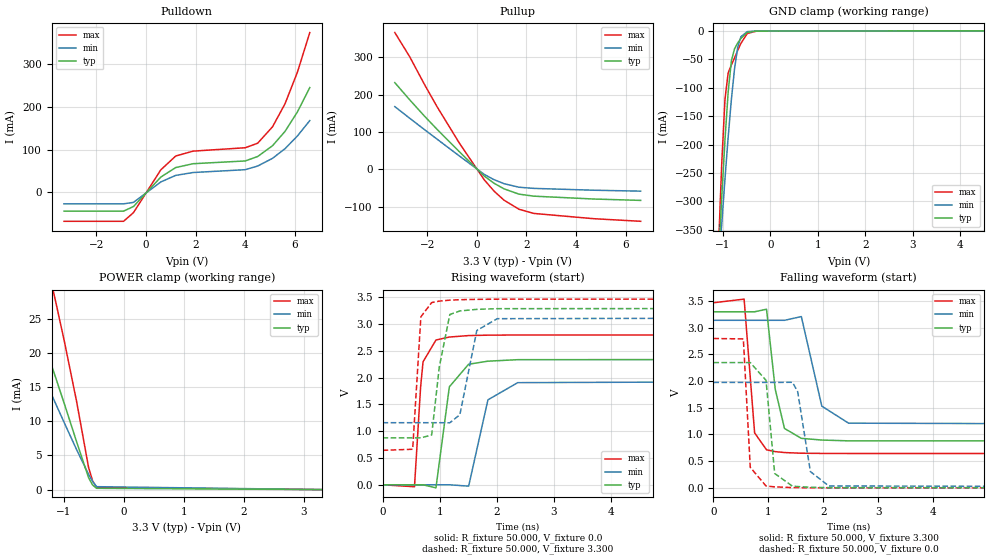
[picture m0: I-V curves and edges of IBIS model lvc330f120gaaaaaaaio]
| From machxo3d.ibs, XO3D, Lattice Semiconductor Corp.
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|   Model lvc330f120gaaaaaaaio
[Model] lvc330f120gaaaaaaaio
Model_type I/O
Polarity   Non-Inverting
Enable   Active-Low
Vinl =  0.800V
Vinh =  2.000V
Vmeas =  1.650V
Cref =  0.0F
Rref =  1.000M
Vref =  0.0V
C_comp   4.200pF   3.800pF   7.500pF
[Temperature Range]   25.000   0.105k   -40.000
[Voltage Range]   3.300V   3.140V   3.470V
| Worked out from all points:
|   slope of the pulldown table from 0 to 0.495 V, typ, clamps not added: 16.2 ohm
|   slope of the pullup table from 0 to 0.495 V, typ, clamps not added: 17.8 ohm
|   GND clamp passes 1 mA (typ) near -0.43 V on its own axis
|   POWER clamp passes 1 mA (typ) near -0.54 V on its own axis
|   rising waveform, R_fixture 50.000, V_fixture 0.0: 20-80 % time 169ps typ, 244ps min, 97.5ps max; typ from 0 V to 2.35 V
|   rising waveform, R_fixture 50.000, V_fixture 3.300: 20-80 % time 130ps typ, 209ps min, 73.1ps max; typ from 0.876 V to 3.3 V
|   falling waveform, R_fixture 50.000, V_fixture 3.300: 20-80 % time 177ps typ, 262ps min, 115ps max; typ from 3.3 V to 0.876 V
|   falling waveform, R_fixture 50.000, V_fixture 0.0: 20-80 % time 108ps typ, 168ps min, 71.9ps max; typ from 2.35 V to 0 V
[Pulldown]
|Voltage   I(typ)   I(min)   I(max)
-3.3V     -43.98mA   -26.85mA   -67.81mA
-900mV    -43.98mA   -26.85mA   -67.81mA
-500mV    -33.06mA   -23.42mA   -47.39mA
600mV     35.86mA    24.47mA    52.84mA
1.2V      58.2mA     39.81mA    85.22mA
1.9V      67.18mA    46.53mA    96.69mA
4V        73.65mA    53.18mA    104.6mA
4.5V      84.05mA    61.72mA    115.2mA
5.1V      109.4mA    79.84mA    153.8mA
5.6V      142.8mA    102.3mA    207.4mA
6.1V      188.4mA    132.1mA    281.4mA
6.6V      245.6mA    168.3mA    374.6mA
[Pullup]
|Voltage   I(typ)   I(min)   I(max)
-3.3V     231.7mA    167.7mA    365.5mA
-2.7V     185.8mA    136.6mA    300.8mA
-2.1V     141.9mA    106mA      226.2mA
-1.6V     107.1mA    80.87mA    167.6mA
-700mV    47.13mA    35.94mA    70.14mA
300mV     -17.73mA   -13.25mA   -27.57mA
700mV     -37.16mA   -27.54mA   -58.24mA
1.1V      -51.98mA   -38.15mA   -82.25mA
1.7V      -66.04mA   -47.59mA   -106.4mA
2.3V      -71.47mA   -50.68mA   -117.6mA
4.7V      -79.06mA   -55.58mA   -131.6mA
6.6V      -82.78mA   -58.05mA   -138.6mA
[GND_clamp]
|Voltage   I(typ)   I(min)   I(max)
-3.3V     -4.507A    -3.482A    -6.263A
-1.089V   -398.4mA   -420.6mA   -374.7mA
-1.022V   -290.7mA   -338.6mA   -230.6mA
-955mV    -191.4mA   -260.2mA   -120.1mA
-888mV    -107.5mA   -187mA     -73.7mA
-821mV    -53mA      -121.4mA   -59.85mA
-754mV    -31.41mA   -66.94mA   -47.47mA
-687mV    -21.17mA   -28.82mA   -34.25mA
-620mV    -13.21mA   -10.23mA   -22mA
-486mV    -2.63mA    -1.112mA   -4.479mA
-285mV    -80.91uA   -42.41uA   -152.3uA
6.6V      121.2uA    55.84uA    291.2uA
[POWER_clamp]
|Voltage   I(typ)   I(min)   I(max)
-3.3V     59.17mA    46.96mA    89.71mA
-1.993V   37.21mA    28.87mA    58.18mA
-1.926V   35.73mA    27.67mA    56.02mA
-1.591V   27.93mA    21.43mA    44.63mA
-1.189V   17.84mA    13.65mA    29.69mA
-1.122V   16.09mA    12.35mA    27.06mA
-988mV    12.53mA    9.74mA     21.66mA
-787mV    7.047mA    5.88mA     12.98mA
-586mV    1.736mA    2.238mA    3.233mA
-519mV    672uA      1.196mA    1.278mA
-452mV    189uA      428.3uA    309.6uA
3.3V      0A         0A         0A
[Ramp]
| variable   typ   min   max
dV/dt_r   1.408/0.167n   1.185/0.244n   1.680/97.219p
dV/dt_f   1.453/0.177n   1.188/0.261n   1.695/0.115n
R_load = 50.000
[Rising Waveform]
R_fixture= 50.000
V_fixture= 0.0
V_fixture_min= 0.0
V_fixture_max= 0.0
|time   V(typ)   V(min)   V(max)
0s        13.01nV    34.25nV    147.9nV
560ps     39.53uV    -5.079uV   -36.37mV
667ps     243.5uV    -5.079uV   1.824V
710ps     143.7uV    -5.079uV   2.297V
936ps     -57.38mV   94.84uV    2.704V
1.171ns   1.831V     150.7uV    2.76V
1.509ns   2.252V     -25.45mV   2.787V
1.847ns   2.309V     1.587V     2.795V
2.369ns   2.337V     1.908V     2.798V
20ns      2.347V     1.975V     2.799V
[Rising Waveform]
R_fixture= 50.000
V_fixture= 3.300
V_fixture_min= 3.140
V_fixture_max= 3.470
|time   V(typ)   V(min)   V(max)
0s        876.5mV    1.16V      643.5mV
528ps     876.5mV    1.16V      663.6mV
672ps     877.2mV    1.16V      3.138V
861ps     930.3mV    1.16V      3.404V
995ps     2.203V     1.16V      3.431V
1.179ns   3.181V     1.158V     3.449V
1.355ns   3.247V     1.309V     3.457V
1.652ns   3.277V     2.882V     3.464V
2.011ns   3.29V      3.103V     3.467V
20ns      3.299V     3.139V     3.468V
[Falling Waveform]
R_fixture= 50.000
V_fixture= 3.300
V_fixture_min= 3.140
V_fixture_max= 3.470
|time   V(typ)   V(min)   V(max)
0s        3.299V     3.139V     3.468V
560ps     3.299V     3.139V     3.536V
751ps     3.299V     3.139V     1.03V
968ps     3.347V     3.139V     713.2mV
1.127ns   1.846V     3.139V     679.1mV
1.295ns   1.113V     3.139V     661.4mV
1.602ns   927.8mV    3.209V     648.9mV
1.975ns   895.7mV    1.531V     645.3mV
2.462ns   880.8mV    1.212V     643.8mV
20ns      876.4mV    1.16V      643.4mV
[Falling Waveform]
R_fixture= 50.000
V_fixture= 0.0
V_fixture_min= 0.0
V_fixture_max= 0.0
|time   V(typ)   V(min)   V(max)
0s        2.347V     1.975V     2.799V
546ps     2.347V     1.975V     2.79V
672ps     2.347V     1.975V     384.7mV
959ps     2.015V     1.975V     34.98mV
1.117ns   269.2mV    1.975V     18.66mV
1.44ns    31.9mV     1.978V     5.105mV
1.535ns   24.35mV    1.804V     3.692mV
1.767ns   10.88mV    304.4mV    1.607mV
2.103ns   4.025mV    35.62mV    412.2uV
20ns      -139.4nV   37.51nV    -50.39nV
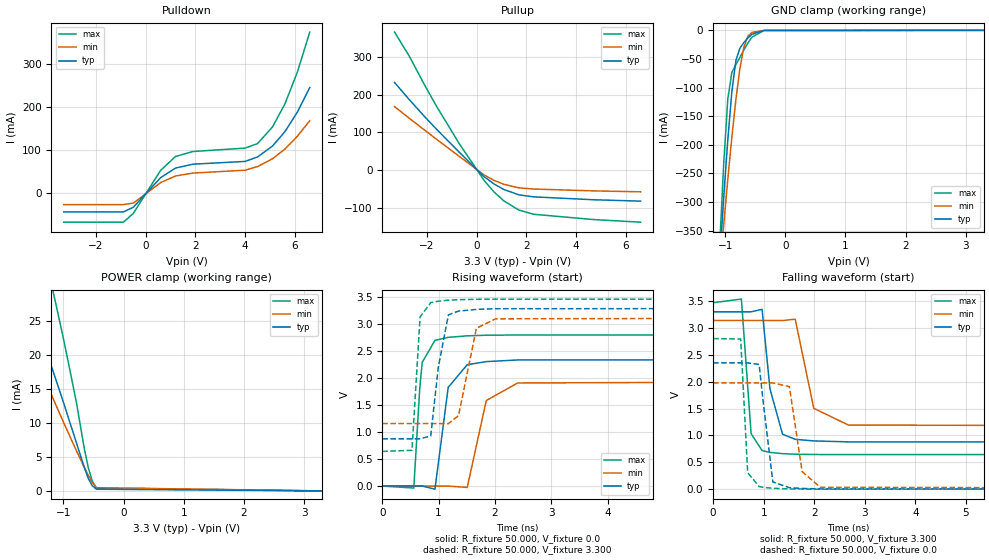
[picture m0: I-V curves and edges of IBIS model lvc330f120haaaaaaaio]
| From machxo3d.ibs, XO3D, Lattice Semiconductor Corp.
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|   Model lvc330f120haaaaaaaio
[Model] lvc330f120haaaaaaaio
Model_type I/O
Polarity   Non-Inverting
Enable   Active-Low
Vinl =  0.800V
Vinh =  2.000V
Vmeas =  1.650V
Cref =  0.0F
Rref =  1.000M
Vref =  0.0V
C_comp   4.200pF   3.800pF   7.500pF
[Temperature Range]   25.000   0.105k   -40.000
[Voltage Range]   3.300V   3.140V   3.470V
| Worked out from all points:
|   slope of the pulldown table from 0 to 0.495 V, typ, clamps not added: 16.2 ohm
|   slope of the pullup table from 0 to 0.495 V, typ, clamps not added: 17.8 ohm
|   GND clamp passes 1 mA (typ) near -0.43 V on its own axis
|   POWER clamp passes 1 mA (typ) near -0.53 V on its own axis
|   rising waveform, R_fixture 50.000, V_fixture 0.0: 20-80 % time 169ps typ, 244ps min, 97.9ps max; typ from 0 V to 2.35 V
|   rising waveform, R_fixture 50.000, V_fixture 3.300: 20-80 % time 131ps typ, 209ps min, 73.3ps max; typ from 0.876 V to 3.3 V
|   falling waveform, R_fixture 50.000, V_fixture 3.300: 20-80 % time 179ps typ, 265ps min, 116ps max; typ from 3.3 V to 0.876 V
|   falling waveform, R_fixture 50.000, V_fixture 0.0: 20-80 % time 108ps typ, 168ps min, 72.4ps max; typ from 2.35 V to 0 V
[Pulldown]
|Voltage   I(typ)   I(min)   I(max)
-3.3V     -43.98mA   -26.85mA   -67.81mA
-900mV    -43.98mA   -26.85mA   -67.81mA
-500mV    -33.06mA   -23.42mA   -47.39mA
600mV     35.86mA    24.47mA    52.84mA
1.2V      58.2mA     39.81mA    85.22mA
1.9V      67.18mA    46.53mA    96.69mA
4V        73.65mA    53.18mA    104.6mA
4.5V      84.05mA    61.72mA    115.2mA
5.1V      109.4mA    79.84mA    153.8mA
5.6V      142.8mA    102.3mA    207.4mA
6.1V      188.4mA    132.1mA    281.4mA
6.6V      245.6mA    168.3mA    374.6mA
[Pullup]
|Voltage   I(typ)   I(min)   I(max)
-3.3V     231.9mA    167.8mA    365.5mA
-2.7V     185.9mA    136.7mA    300.8mA
-2.1V     142mA      106.1mA    226.2mA
-1.6V     107.1mA    80.87mA    167.6mA
-700mV    47.13mA    35.94mA    70.14mA
300mV     -17.73mA   -13.25mA   -27.57mA
700mV     -37.16mA   -27.54mA   -58.24mA
1.1V      -51.98mA   -38.15mA   -82.25mA
1.7V      -66.04mA   -47.59mA   -106.4mA
2.3V      -71.47mA   -50.68mA   -117.6mA
4.7V      -79.06mA   -55.58mA   -131.6mA
6.6V      -82.78mA   -58.05mA   -138.6mA
[GND_clamp]
|Voltage   I(typ)   I(min)   I(max)
-3.3V     -4.507A    -3.482A    -6.263A
-1.089V   -398.4mA   -420.6mA   -374.7mA
-1.022V   -290.7mA   -338.6mA   -230.6mA
-955mV    -191.4mA   -260.2mA   -120.1mA
-888mV    -107.5mA   -187mA     -73.7mA
-821mV    -53mA      -121.4mA   -59.85mA
-754mV    -31.41mA   -66.94mA   -47.47mA
-687mV    -21.17mA   -28.82mA   -34.25mA
-620mV    -13.21mA   -10.23mA   -22mA
-553mV    -6.875mA   -3.578mA   -11.73mA
-352mV    -176.3uA   -89.98uA   -279uA
3.3V      50.87nA    0A         -26.43uA
[POWER_clamp]
|Voltage   I(typ)   I(min)   I(max)
-3.3V     62.1mA     51.02mA    92.7mA
-1.926V   36.35mA    28.59mA    56.55mA
-1.591V   28.28mA    21.98mA    45.01mA
-1.189V   18.03mA    13.9mA     29.96mA
-1.122V   16.26mA    12.55mA    27.31mA
-988mV    12.68mA    9.882mA    21.88mA
-787mV    7.154mA    5.963mA    13.15mA
-653mV    3.439mA    3.462mA    6.207mA
-586mV    1.819mA    2.29mA     3.395mA
-519mV    748.7uA    1.242mA    1.434mA
-452mV    255.4uA    468.1uA    442.9uA
3.3V      0A         0A         0A
[Ramp]
| variable   typ   min   max
dV/dt_r   1.410/0.168n   1.187/0.244n   1.682/97.563p
dV/dt_f   1.454/0.178n   1.188/0.263n   1.696/0.116n
R_load = 50.000
[Rising Waveform]
R_fixture= 50.000
V_fixture= 0.0
V_fixture_min= 0.0
V_fixture_max= 0.0
|time   V(typ)   V(min)   V(max)
0s        13.01nV    34.25nV    147.9nV
560ps     39.52uV    -5.096uV   -36.37mV
667ps     243.5uV    -5.096uV   1.824V
710ps     143.7uV    -5.096uV   2.297V
936ps     -57.38mV   94.84uV    2.704V
1.171ns   1.831V     150.7uV    2.76V
1.509ns   2.252V     -25.45mV   2.788V
1.847ns   2.309V     1.587V     2.799V
2.403ns   2.34V      1.913V     2.803V
20ns      2.351V     1.978V     2.803V
[Rising Waveform]
R_fixture= 50.000
V_fixture= 3.300
V_fixture_min= 3.140
V_fixture_max= 3.470
|time   V(typ)   V(min)   V(max)
0s        876.5mV    1.16V      643.5mV
528ps     876.5mV    1.16V      663.6mV
672ps     877.2mV    1.16V      3.138V
861ps     930.3mV    1.16V      3.404V
995ps     2.203V     1.16V      3.431V
1.175ns   3.177V     1.158V     3.45V
1.355ns   3.247V     1.309V     3.458V
1.672ns   3.278V     2.928V     3.466V
2.011ns   3.291V     3.103V     3.469V
20ns      3.3V       3.14V      3.47V
[Falling Waveform]
R_fixture= 50.000
V_fixture= 3.300
V_fixture_min= 3.140
V_fixture_max= 3.470
|time   V(typ)   V(min)   V(max)
0s        3.3V       3.14V      3.47V
560ps     3.3V       3.14V      3.538V
752ps     3.301V     3.14V      1.034V
969ps     3.346V     3.14V      717.6mV
1.125ns   1.867V     3.14V      684.7mV
1.374ns   1.022V     3.138V     661.2mV
1.624ns   928.5mV    3.164V     650.6mV
1.991ns   897.8mV    1.505V     645.4mV
2.676ns   880.4mV    1.193V     643.6mV
20ns      876.4mV    1.16V      643.5mV
[Falling Waveform]
R_fixture= 50.000
V_fixture= 0.0
V_fixture_min= 0.0
V_fixture_max= 0.0
|time   V(typ)   V(min)   V(max)
0s        2.351V     1.978V     2.803V
546ps     2.351V     1.978V     2.794V
685ps     2.35V      1.978V     305.6mV
911ps     2.321V     1.978V     47.27mV
987ps     1.655V     1.978V     33.63mV
1.182ns   134.2mV    1.978V     15.74mV
1.509ns   27.45mV    1.908V     4.448mV
1.761ns   13.5mV     327.2mV    1.879mV
2.118ns   4.697mV    35.37mV    544.2uV
20ns      29.43nV    161.9nV    62.39nV
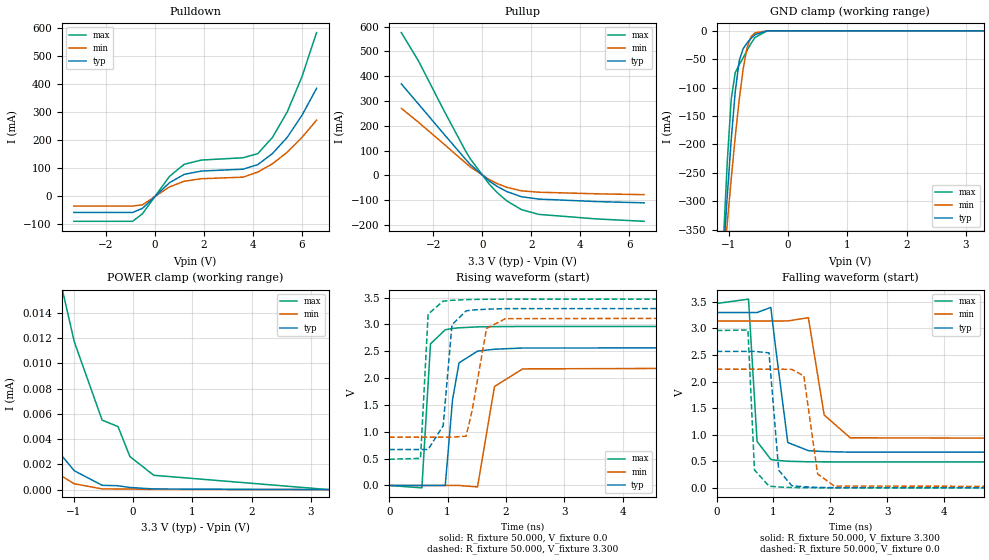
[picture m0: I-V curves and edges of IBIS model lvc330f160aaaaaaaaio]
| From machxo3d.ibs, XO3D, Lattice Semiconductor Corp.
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|   Model lvc330f160aaaaaaaaio
[Model] lvc330f160aaaaaaaaio
Model_type I/O
Polarity   Non-Inverting
Enable   Active-Low
Vinl =  0.800V
Vinh =  2.000V
Vmeas =  1.650V
Cref =  0.0F
Rref =  1.000M
Vref =  0.0V
C_comp   4.200pF   3.800pF   7.500pF
[Temperature Range]   25.000   0.105k   -40.000
[Voltage Range]   3.300V   3.140V   3.470V
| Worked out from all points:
|   slope of the pulldown table from 0 to 0.495 V, typ, clamps not added: 12.2 ohm
|   slope of the pullup table from 0 to 0.495 V, typ, clamps not added: 13.4 ohm
|   GND clamp passes 1 mA (typ) near -0.43 V on its own axis
|   rising waveform, R_fixture 50.000, V_fixture 0.0: 20-80 % time 129ps typ, 192ps min, 74.4ps max; typ from 0 V to 2.57 V
|   rising waveform, R_fixture 50.000, V_fixture 3.300: 20-80 % time 113ps typ, 192ps min, 61.2ps max; typ from 0.669 V to 3.3 V
|   falling waveform, R_fixture 50.000, V_fixture 3.300: 20-80 % time 133ps typ, 204ps min, 85.3ps max; typ from 3.3 V to 0.669 V
|   falling waveform, R_fixture 50.000, V_fixture 0.0: 20-80 % time 92ps typ, 149ps min, 60.4ps max; typ from 2.57 V to 0 V
[Pulldown]
|Voltage   I(typ)   I(min)   I(max)
-3.3V     -58.64mA   -35.81mA   -90.41mA
-900mV    -58.64mA   -35.81mA   -90.41mA
-500mV    -44.08mA   -31.23mA   -63.19mA
600mV     47.81mA    32.63mA    70.46mA
1.2V      77.59mA    53.08mA    113.6mA
1.9V      89.57mA    62.04mA    128.9mA
3.6V      96.17mA    67.68mA    137.1mA
4.2V      112.5mA    85.73mA    151.8mA
4.8V      152.1mA    115.6mA    210mA
5.4V      210.1mA    156.8mA    300.9mA
6V        288.6mA    209.7mA    426.8mA
6.6V      385.9mA    271.8mA    585.4mA
[Pullup]
|Voltage   I(typ)   I(min)   I(max)
-3.3V     369mA      270.5mA    575.9mA
-2.6V     287.7mA    214.3mA    461.4mA
-1.6V     171mA      129.5mA    268.6mA
-700mV    67.51mA    52.18mA    102mA
-500mV    45.31mA    35.18mA    68.54mA
300mV     -23.64mA   -17.66mA   -36.76mA
600mV     -43.66mA   -32.42mA   -68.28mA
1V        -64.93mA   -47.78mA   -102.5mA
1.6V      -85.8mA    -62.05mA   -137.8mA
2.3V      -95.3mA    -67.57mA   -156.9mA
4.7V      -105.4mA   -74.1mA    -175.5mA
6.6V      -110.4mA   -77.4mA    -184.8mA
[GND_clamp]
|Voltage   I(typ)   I(min)   I(max)
-3.3V     -4.507A    -3.482A    -6.263A
-1.089V   -398.4mA   -420.6mA   -374.7mA
-1.022V   -290.7mA   -338.6mA   -230.6mA
-955mV    -191.3mA   -260.2mA   -120mA
-888mV    -107.5mA   -187mA     -73.64mA
-821mV    -52.96mA   -121.4mA   -59.79mA
-754mV    -31.36mA   -66.92mA   -47.4mA
-687mV    -21.12mA   -28.79mA   -34.18mA
-620mV    -13.16mA   -10.19mA   -21.93mA
-553mV    -6.814mA   -3.53mA    -11.64mA
-352mV    -96.36uA   -46.21uA   -149.8uA
3.3V      0A         0A         0A
[POWER_clamp]
|Voltage   I(typ)   I(min)   I(max)
-3.3V     732.2uA    455.9uA    1.265mA
-2.663V   69.44uA    15.46uA    306.8uA
-2.529V   27.69uA    10.95uA    164.1uA
-2.328V   15.69uA    8.497uA    64.68uA
-1.725V   7.348uA    3.693uA    30.69uA
-1.189V   2.632uA    1.04uA     15.85uA
-988mV    1.494uA    463.1nA    11.72uA
-519mV    342.8nA    54.75nA    5.51uA
-251mV    305.1nA    47.62nA    4.994uA
-50mV     169nA      47.62nA    2.616uA
352mV     50.67nA    4.149nA    1.135uA
3.3V      0A         0A         0A
[Ramp]
| variable   typ   min   max
dV/dt_r   1.541/0.128n   1.340/0.192n   1.777/74.338p
dV/dt_f   1.578/0.133n   1.344/0.203n   1.789/85.229p
R_load = 50.000
[Rising Waveform]
R_fixture= 50.000
V_fixture= 0.0
V_fixture_min= 0.0
V_fixture_max= 0.0
|time   V(typ)   V(min)   V(max)
0s        10.54nV    27.99nV    119.6nV
560ps     35uV       15.39uV    -44.65mV
708ps     966nV      15.39uV    2.636V
961ps     680.8uV    101.4uV    2.9V
1.086ns   1.598V     171.8uV    2.924V
1.197ns   2.283V     -42.1uV    2.936V
1.514ns   2.501V     -27.25mV   2.953V
1.805ns   2.537V     1.843V     2.958V
2.289ns   2.56V      2.171V     2.961V
20ns      2.568V     2.233V     2.961V
[Rising Waveform]
R_fixture= 50.000
V_fixture= 3.300
V_fixture_min= 3.140
V_fixture_max= 3.470
|time   V(typ)   V(min)   V(max)
0s        669.4mV    899.2mV    487.7mV
537ps     669.4mV    899.2mV    504.6mV
667ps     669.8mV    899.2mV    3.19V
925ps     1.112V     899.2mV    3.433V
1.076ns   2.991V     900.1mV    3.448V
1.319ns   3.252V     918.3mV    3.461V
1.422ns   3.266V     1.398V     3.464V
1.669ns   3.283V     2.924V     3.467V
1.991ns   3.293V     3.106V     3.469V
20ns      3.3V       3.14V      3.47V
[Falling Waveform]
R_fixture= 50.000
V_fixture= 3.300
V_fixture_min= 3.140
V_fixture_max= 3.470
|time   V(typ)   V(min)   V(max)
0s        3.3V       3.14V      3.47V
560ps     3.3V       3.14V      3.552V
711ps     3.3V       3.14V      872.6mV
953ps     3.396V     3.14V      535.2mV
1.03ns    2.702V     3.14V      521.5mV
1.252ns   853.1mV    3.141V     500.9mV
1.614ns   700.2mV    3.203V     490.8mV
1.892ns   682.8mV    1.372V     488.8mV
2.351ns   672.7mV    942.2mV    487.7mV
20ns      669.4mV    899.1mV    487.4mV
[Falling Waveform]
R_fixture= 50.000
V_fixture= 0.0
V_fixture_min= 0.0
V_fixture_max= 0.0
|time   V(typ)   V(min)   V(max)
0s        2.568V     2.233V     2.961V
550ps     2.568V     2.233V     2.971V
665ps     2.568V     2.233V     337.9mV
921ps     2.541V     2.233V     32.63mV
1.092ns   331.6mV    2.233V     15.91mV
1.321ns   41.67mV    2.231V     6.093mV
1.534ns   19.68mV    2.106V     2.859mV
1.777ns   8.706mV    261.2mV    1.084mV
2.071ns   3.518mV    34.12mV    356.9uV
20ns      43.46nV    -21.22nV   81.17nV
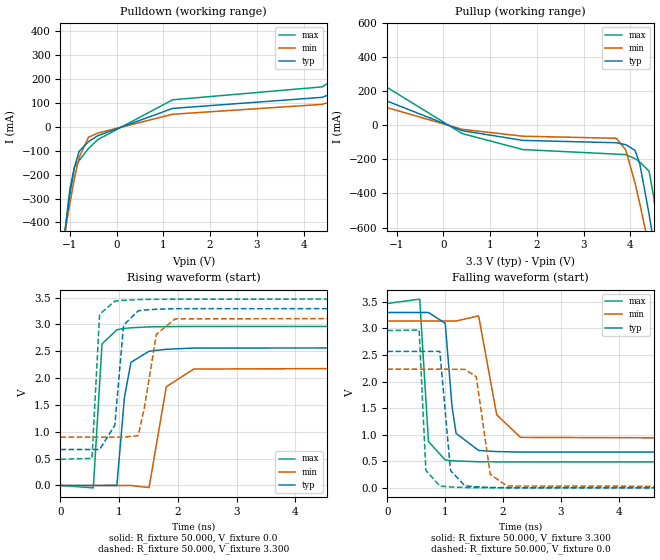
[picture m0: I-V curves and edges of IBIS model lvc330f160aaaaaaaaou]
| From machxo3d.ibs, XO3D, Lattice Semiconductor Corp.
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|   Model lvc330f160aaaaaaaaou
[Model] lvc330f160aaaaaaaaou
Model_type Output
Polarity   Non-Inverting
Enable   Active-High
Vmeas =  1.650V
Cref =  0.0F
Rref =  1.000M
Vref =  0.0V
C_comp   4.200pF   3.800pF   7.500pF
[Temperature Range]   25.000   0.105k   -40.000
[Voltage Range]   3.300V   3.140V   3.470V
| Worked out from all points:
|   slope of the pulldown table from 0 to 0.495 V, typ, clamps not added: 12.2 ohm
|   slope of the pullup table from 0 to 0.495 V, typ, clamps not added: 13.4 ohm
|   rising waveform, R_fixture 50.000, V_fixture 0.0: 20-80 % time 129ps typ, 191ps min, 74.4ps max; typ from 0 V to 2.57 V
|   rising waveform, R_fixture 50.000, V_fixture 3.300: 20-80 % time 113ps typ, 192ps min, 61.2ps max; typ from 0.669 V to 3.3 V
|   falling waveform, R_fixture 50.000, V_fixture 3.300: 20-80 % time 133ps typ, 204ps min, 85.3ps max; typ from 3.3 V to 0.669 V
|   falling waveform, R_fixture 50.000, V_fixture 0.0: 20-80 % time 92ps typ, 149ps min, 60.4ps max; typ from 2.57 V to 0 V
[Pulldown]
|Voltage   I(typ)   I(min)   I(max)
-3.3V     -4.508A    -3.483A    -6.264A
-1.1V     -430mA     -440.6mA   -433.4mA
-1V       -282.5mA   -321.4mA   -261.3mA
-900mV    -168mA     -213.9mA   -168.3mA
-800mV    -102.2mA   -127.5mA   -140.6mA
-600mV    -61.55mA   -43.25mA   -90.15mA
-400mV    -36.57mA   -25.48mA   -52.9mA
1.2V      77.59mA    53.08mA    113.6mA
4.4V      123.9mA    94.46mA    167.7mA
5.2V      188.6mA    141.7mA    266.7mA
6V        288.7mA    209.8mA    427mA
6.6V      386.7mA    272.5mA    586.4mA
[Pullup]
|Voltage   I(typ)   I(min)   I(max)
-3.3V     369.7mA    271mA      577.1mA
400mV     -30.71mA   -22.9mA    -47.84mA
1.7V      -88.05mA   -63.45mA   -141.9mA
3.7V      -101.9mA   -75.64mA   -168.8mA
3.9V      -113.4mA   -143.5mA   -171.4mA
4.1V      -146.7mA   -338.6mA   -195.1mA
4.2V      -224.3mA   -457.7mA   -214.8mA
4.4V      -521mA     -713.3mA   -268.6mA
4.5V      -691.6mA   -845.9mA   -420.8mA
4.6V      -867.9mA   -980.3mA   -645.1mA
4.7V      -1.048A    -1.116A    -890.7mA
6.6V      -4.617A    -3.787A    -5.985A
[Ramp]
| variable   typ   min   max
dV/dt_r   1.541/0.128n   1.340/0.192n   1.777/74.329p
dV/dt_f   1.578/0.133n   1.344/0.203n   1.789/85.236p
R_load = 50.000
[Rising Waveform]
R_fixture= 50.000
V_fixture= 0.0
V_fixture_min= 0.0
V_fixture_max= 0.0
|time   V(typ)   V(min)   V(max)
0s        10.54nV    27.99nV    119.6nV
560ps     35.18uV    14.61uV    -44.65mV
708ps     -5.833uV   14.61uV    2.636V
961ps     686.2uV    100.3uV    2.9V
1.09ns    1.644V     169.4uV    2.924V
1.201ns   2.293V     -180.9uV   2.936V
1.509ns   2.5V       -38.75mV   2.953V
1.803ns   2.536V     1.838V     2.958V
2.269ns   2.559V     2.168V     2.961V
20ns      2.568V     2.233V     2.961V
[Rising Waveform]
R_fixture= 50.000
V_fixture= 3.300
V_fixture_min= 3.140
V_fixture_max= 3.470
|time   V(typ)   V(min)   V(max)
0s        669.4mV    899.2mV    487.7mV
537ps     669.4mV    899.2mV    504.6mV
667ps     669.8mV    899.2mV    3.19V
926ps     1.122V     899.2mV    3.433V
1.075ns   2.986V     900mV      3.448V
1.325ns   3.253V     927.6mV    3.461V
1.43ns    3.267V     1.451V     3.464V
1.634ns   3.282V     2.815V     3.467V
1.953ns   3.292V     3.102V     3.469V
20ns      3.3V       3.14V      3.47V
[Falling Waveform]
R_fixture= 50.000
V_fixture= 3.300
V_fixture_min= 3.140
V_fixture_max= 3.470
|time   V(typ)   V(min)   V(max)
0s        3.3V       3.14V      3.47V
560ps     3.3V       3.14V      3.552V
711ps     3.3V       3.14V      872.6mV
1.001ns   3.097V     3.14V      525.1mV
1.118ns   1.536V     3.14V      510.8mV
1.189ns   1.026V     3.14V      505.8mV
1.578ns   704mV      3.237V     491.1mV
1.891ns   682.7mV    1.375V     488.8mV
2.303ns   673.6mV    949.2mV    487.7mV
20ns      669.4mV    899.1mV    487.4mV
[Falling Waveform]
R_fixture= 50.000
V_fixture= 0.0
V_fixture_min= 0.0
V_fixture_max= 0.0
|time   V(typ)   V(min)   V(max)
0s        2.568V     2.233V     2.961V
550ps     2.568V     2.233V     2.971V
666ps     2.568V     2.233V     329.6mV
908ps     2.567V     2.233V     34.18mV
1.093ns   326mV      2.232V     16.46mV
1.34ns    38.25mV    2.231V     5.749mV
1.537ns   19.69mV    2.092V     2.633mV
1.78ns    8.978mV    252.3mV    1.173mV
2.071ns   3.608mV    34.11mV    435uV
20ns      -261.5nV   -87.57nV   -52.68nV
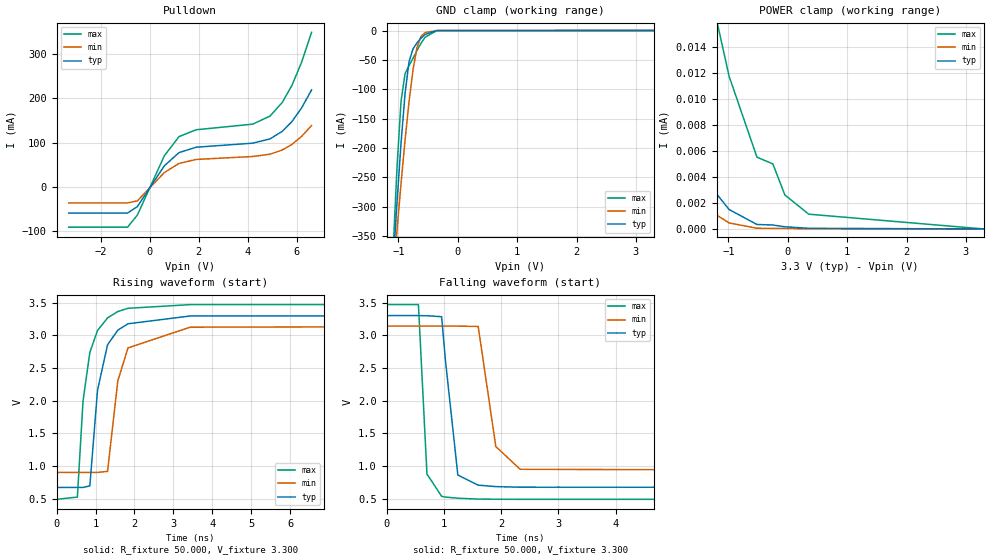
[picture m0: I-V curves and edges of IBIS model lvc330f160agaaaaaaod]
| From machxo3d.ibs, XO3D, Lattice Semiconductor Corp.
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|   Model lvc330f160agaaaaaaod
[Model] lvc330f160agaaaaaaod
Model_type I/O_open_drain
Polarity   Non-Inverting
Enable   Active-Low
Vinl =  0.800V
Vinh =  2.000V
Vmeas =  1.650V
Cref =  0.0F
Rref = 10.00k
Vref = 3.30V
C_comp   4.200pF   3.800pF   7.500pF
[Temperature Range]   25.000   0.105k   -40.000
[Voltage Range]   3.300V   3.140V   3.470V
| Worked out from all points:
|   slope of the pulldown table from 0 to 0.495 V, typ, clamps not added: 12.2 ohm
|   GND clamp passes 1 mA (typ) near -0.43 V on its own axis
|   rising waveform, R_fixture 50.000, V_fixture 3.300: 20-80 % time 328ps typ, 330ps min, 332ps max; typ from 0.669 V to 3.3 V
|   falling waveform, R_fixture 50.000, V_fixture 3.300: 20-80 % time 136ps typ, 207ps min, 87ps max; typ from 3.3 V to 0.669 V
[Pulldown]
|Voltage   I(typ)   I(min)   I(max)
-3.3V     -58.64mA   -35.81mA   -90.41mA
-900mV    -58.64mA   -35.81mA   -90.41mA
-500mV    -44.08mA   -31.23mA   -63.19mA
600mV     47.81mA    32.63mA    70.46mA
1.2V      77.59mA    53.08mA    113.6mA
1.9V      89.57mA    62.04mA    128.9mA
4.2V      98.64mA    68.65mA    141.5mA
4.9V      108.2mA    73.77mA    159.5mA
5.4V      125.1mA    83.07mA    190mA
5.8V      147.4mA    95.86mA    228.9mA
6.2V      178.7mA    114.3mA    281.9mA
6.6V      218.6mA    138.5mA    348.2mA
[GND_clamp]
|Voltage   I(typ)   I(min)   I(max)
-3.3V     -4.507A    -3.482A    -6.263A
-1.089V   -398.4mA   -420.6mA   -374.6mA
-1.022V   -290.7mA   -338.6mA   -230.5mA
-955mV    -191.3mA   -260.2mA   -120mA
-888mV    -107.4mA   -187mA     -73.61mA
-821mV    -52.94mA   -121.4mA   -59.76mA
-754mV    -31.35mA   -66.91mA   -47.37mA
-687mV    -21.1mA    -28.79mA   -34.15mA
-620mV    -13.15mA   -10.18mA   -21.9mA
-553mV    -6.805mA   -3.528mA   -11.62mA
-352mV    -95.59uA   -46.15uA   -145.6uA
3.3V      0A         0A         0A
[POWER_clamp]
|Voltage   I(typ)   I(min)   I(max)
-3.3V     732.2uA    455.9uA    1.265mA
-2.663V   69.44uA    15.46uA    306.8uA
-2.529V   27.69uA    10.95uA    164.1uA
-2.328V   15.69uA    8.498uA    64.68uA
-1.725V   7.348uA    3.693uA    30.69uA
-1.189V   2.632uA    1.04uA     15.85uA
-988mV    1.494uA    463.1nA    11.72uA
-519mV    342.8nA    54.76nA    5.51uA
-251mV    305.1nA    47.63nA    4.994uA
-50mV     169nA      47.63nA    2.616uA
352mV     50.68nA    4.163nA    1.135uA
3.3V      0A         0A         0A
[Ramp]
| variable   typ   min   max
dV/dt_r   1.578/0.329n   1.344/0.328n   1.789/0.331n
dV/dt_f   1.578/0.135n   1.344/0.207n   1.789/86.906p
R_load = 50.000
[Rising Waveform]
R_fixture= 50.000
V_fixture= 3.300
V_fixture_min= 3.140
V_fixture_max= 3.470
|time   V(typ)   V(min)   V(max)
0s        669.4mV    899.2mV    487.7mV
535ps     669.4mV    899.2mV    522.3mV
680ps     670mV      899.2mV    1.993V
855ps     694.1mV    899.2mV    2.738V
1.052ns   2.158V     899.9mV    3.072V
1.309ns   2.854V     915.6mV    3.265V
1.573ns   3.077V     2.303V     3.363V
1.834ns   3.175V     2.806V     3.412V
3.428ns   3.294V     3.123V     3.468V
20ns      3.3V       3.14V      3.47V
[Falling Waveform]
R_fixture= 50.000
V_fixture= 3.300
V_fixture_min= 3.140
V_fixture_max= 3.470
|time   V(typ)   V(min)   V(max)
0s        3.3V       3.14V      3.47V
557ps     3.3V       3.14V      3.469V
706ps     3.298V     3.14V      874.8mV
962ps     3.283V     3.14V      534mV
1.028ns   2.62V      3.14V      521.9mV
1.245ns   859.5mV    3.139V     504.7mV
1.601ns   704.5mV    3.134V     491mV
1.908ns   682.2mV    1.296V     488.8mV
2.333ns   673.3mV    947.5mV    487.8mV
20ns      669.3mV    899.1mV    487.5mV
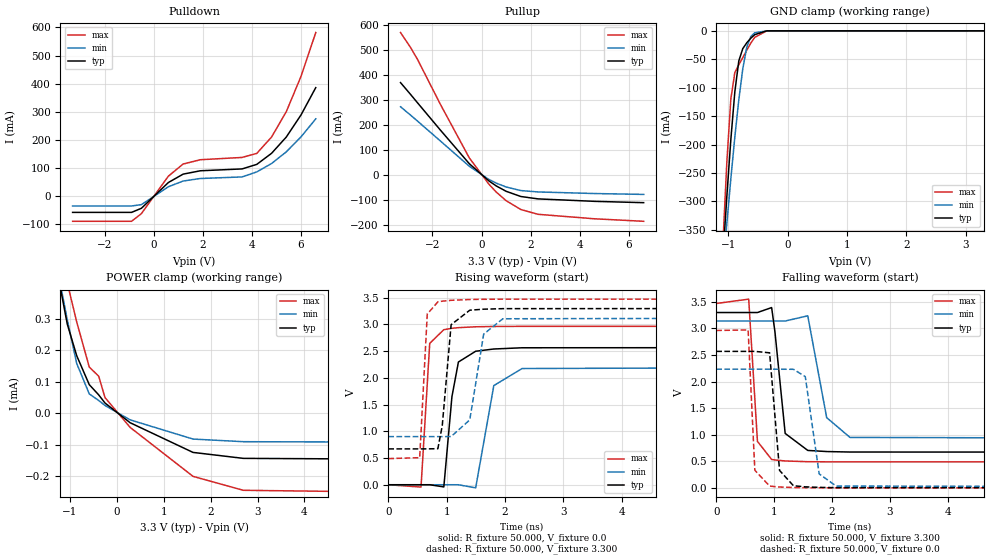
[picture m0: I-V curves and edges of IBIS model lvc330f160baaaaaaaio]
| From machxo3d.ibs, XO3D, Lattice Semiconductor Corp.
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|   Model lvc330f160baaaaaaaio
[Model] lvc330f160baaaaaaaio
Model_type I/O
Polarity   Non-Inverting
Enable   Active-Low
Vinl =  0.800V
Vinh =  2.000V
Vmeas =  1.650V
Cref =  0.0F
Rref =  1.000M
Vref =  0.0V
C_comp   4.200pF   3.800pF   7.500pF
[Temperature Range]   25.000   0.105k   -40.000
[Voltage Range]   3.300V   3.140V   3.470V
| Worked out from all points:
|   slope of the pulldown table from 0 to 0.495 V, typ, clamps not added: 12.2 ohm
|   slope of the pullup table from 0 to 0.495 V, typ, clamps not added: 13.4 ohm
|   GND clamp passes 1 mA (typ) near -0.43 V on its own axis
|   POWER clamp passes 1 mA (typ) near -1.85 V on its own axis
|   rising waveform, R_fixture 50.000, V_fixture 0.0: 20-80 % time 129ps typ, 192ps min, 74.3ps max; typ from 0.001 V to 2.57 V
|   rising waveform, R_fixture 50.000, V_fixture 3.300: 20-80 % time 113ps typ, 192ps min, 61.2ps max; typ from 0.671 V to 3.3 V
|   falling waveform, R_fixture 50.000, V_fixture 3.300: 20-80 % time 134ps typ, 203ps min, 85.4ps max; typ from 3.3 V to 0.671 V
|   falling waveform, R_fixture 50.000, V_fixture 0.0: 20-80 % time 92.2ps typ, 149ps min, 60.5ps max; typ from 2.57 V to 0.001 V
[Pulldown]
|Voltage   I(typ)   I(min)   I(max)
-3.3V     -58.64mA   -35.81mA   -90.41mA
-900mV    -58.64mA   -35.81mA   -90.41mA
-500mV    -44.08mA   -31.23mA   -63.19mA
600mV     47.81mA    32.63mA    70.46mA
1.2V      77.59mA    53.08mA    113.6mA
1.9V      89.57mA    62.04mA    128.9mA
3.6V      96.17mA    67.67mA    137.1mA
4.2V      112.4mA    85.6mA     151.6mA
4.8V      151.7mA    115.4mA    209.7mA
5.4V      209.7mA    156.9mA    300.1mA
6V        288.5mA    210.5mA    426mA
6.6V      385.8mA    274.4mA    581.9mA
[Pullup]
|Voltage   I(typ)   I(min)   I(max)
-3.3V     369.2mA    272.8mA    569.1mA
-2.9V     323mA      240mA      510.9mA
-2.6V     287.6mA    214.8mA    460.5mA
-1.7V     182.2mA    137.9mA    286.7mA
-500mV    45.28mA    35.17mA    68.49mA
300mV     -23.64mA   -17.66mA   -36.76mA
600mV     -43.66mA   -32.42mA   -68.28mA
1V        -64.93mA   -47.78mA   -102.5mA
1.6V      -85.8mA    -62.05mA   -137.8mA
2.3V      -95.3mA    -67.57mA   -156.9mA
4.6V      -105.1mA   -73.89mA   -174.8mA
6.6V      -110.4mA   -77.4mA    -184.8mA
[GND_clamp]
|Voltage   I(typ)   I(min)   I(max)
-3.3V     -4.506A    -3.482A    -6.262A
-1.089V   -398.3mA   -420.5mA   -374.5mA
-1.022V   -290.6mA   -338.5mA   -230.4mA
-955mV    -191.2mA   -260.1mA   -119.8mA
-888mV    -107.4mA   -186.9mA   -73.47mA
-821mV    -52.87mA   -121.3mA   -59.62mA
-754mV    -31.28mA   -66.86mA   -47.24mA
-687mV    -21.04mA   -28.74mA   -34.02mA
-620mV    -13.09mA   -10.15mA   -21.79mA
-553mV    -6.755mA   -3.505mA   -11.52mA
-352mV    -90.18uA   -45.39uA   -119.9uA
3.3V      0A         0A         0A
[POWER_clamp]
|Voltage   I(typ)   I(min)   I(max)
-3.3V     3.967mA    2.512mA    11.53mA
-1.323V   507.3uA    506.4uA    605.6uA
-1.189V   387.7uA    399.8uA    501.1uA
-1.055V   282.8uA    296.7uA    413.8uA
-854mV    182.6uA    158.2uA    289.7uA
-586mV    90.73uA    61.33uA    146.6uA
-385mV    58.36uA    40.66uA    117.5uA
-251mV    32.53uA    24.74uA    49.87uA
285mV     -29.95uA   -20.85uA   -44.72uA
1.625V    -124uA     -81.72uA   -199.9uA
2.697V    -142.9uA   -90.03uA   -244.1uA
6.6V      -145.9uA   -91.75uA   -251.2uA
[Ramp]
| variable   typ   min   max
dV/dt_r   1.541/0.128n   1.340/0.191n   1.776/74.192p
dV/dt_f   1.577/0.133n   1.344/0.203n   1.788/85.356p
R_load = 50.000
[Rising Waveform]
R_fixture= 50.000
V_fixture= 0.0
V_fixture_min= 0.0
V_fixture_max= 0.0
|time   V(typ)   V(min)   V(max)
0s        1.249mV    1.066mV    1.539mV
560ps     1.284mV    1.079mV    -42.6mV
709ps     1.244mV    1.079mV    2.643V
951ps     -39.4mV    1.169mV    2.899V
1.09ns    1.648V     1.234mV    2.925V
1.201ns   2.295V     874.4uV    2.937V
1.497ns   2.496V     -57.01mV   2.953V
1.808ns   2.538V     1.854V     2.959V
2.293ns   2.561V     2.173V     2.961V
20ns      2.569V     2.234V     2.962V
[Rising Waveform]
R_fixture= 50.000
V_fixture= 3.300
V_fixture_min= 3.140
V_fixture_max= 3.470
|time   V(typ)   V(min)   V(max)
0s        671.1mV    900.8mV    489.6mV
537ps     671.2mV    900.8mV    507.1mV
667ps     671.5mV    900.8mV    3.191V
849ps     675.1mV    900.8mV    3.419V
924ps     1.105V     900.8mV    3.432V
1.076ns   2.992V     901.7mV    3.448V
1.396ns   3.263V     1.214V     3.463V
1.634ns   3.282V     2.816V     3.467V
1.963ns   3.292V     3.103V     3.469V
20ns      3.3V       3.14V      3.47V
[Falling Waveform]
R_fixture= 50.000
V_fixture= 3.300
V_fixture_min= 3.140
V_fixture_max= 3.470
|time   V(typ)   V(min)   V(max)
0s        3.3V       3.14V      3.47V
560ps     3.3V       3.14V      3.552V
711ps     3.3V       3.14V      875.6mV
956ps     3.393V     3.14V      535.6mV
1.014ns   2.93V      3.14V      525.6mV
1.19ns    1.025V     3.14V      507.4mV
1.58ns    705.7mV    3.238V     493.2mV
1.907ns   684.3mV    1.322V     490.9mV
2.31ns    675.2mV    950.1mV    489.8mV
20ns      671.1mV    900.8mV    489.5mV
[Falling Waveform]
R_fixture= 50.000
V_fixture= 0.0
V_fixture_min= 0.0
V_fixture_max= 0.0
|time   V(typ)   V(min)   V(max)
0s        2.569V     2.234V     2.962V
550ps     2.569V     2.234V     2.972V
666ps     2.569V     2.234V     332.2mV
921ps     2.542V     2.234V     34.25mV
1.093ns   328.6mV    2.233V     17.03mV
1.333ns   40.88mV    2.232V     7.326mV
1.537ns   20.28mV    2.094V     4.191mV
1.777ns   9.973mV    263.5mV    2.728mV
2.071ns   4.779mV    35.31mV    1.989mV
20ns      1.249mV    1.066mV    1.538mV
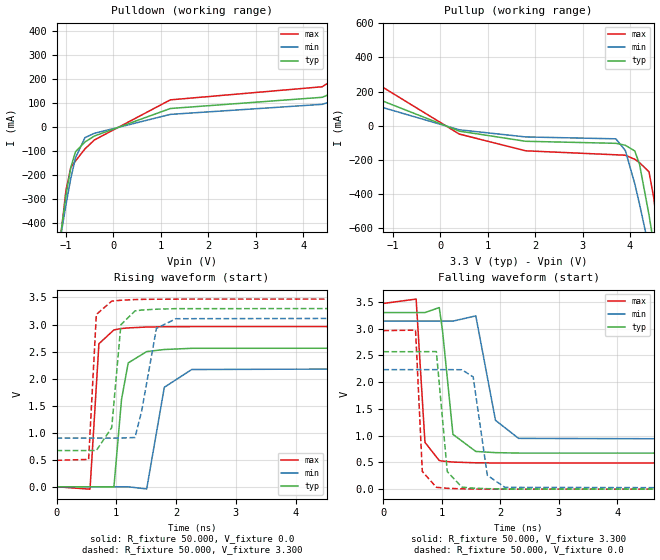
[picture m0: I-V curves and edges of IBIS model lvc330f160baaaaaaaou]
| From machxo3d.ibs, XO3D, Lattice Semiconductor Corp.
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|   Model lvc330f160baaaaaaaou
[Model] lvc330f160baaaaaaaou
Model_type Output
Polarity   Non-Inverting
Enable   Active-High
Vmeas =  1.650V
Cref =  0.0F
Rref =  1.000M
Vref =  0.0V
C_comp   4.200pF   3.800pF   7.500pF
[Temperature Range]   25.000   0.105k   -40.000
[Voltage Range]   3.300V   3.140V   3.470V
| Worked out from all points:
|   slope of the pulldown table from 0 to 0.495 V, typ, clamps not added: 12.2 ohm
|   slope of the pullup table from 0 to 0.495 V, typ, clamps not added: 13.3 ohm
|   rising waveform, R_fixture 50.000, V_fixture 0.0: 20-80 % time 129ps typ, 192ps min, 74.4ps max; typ from 0.001 V to 2.57 V
|   rising waveform, R_fixture 50.000, V_fixture 3.300: 20-80 % time 113ps typ, 193ps min, 61.2ps max; typ from 0.671 V to 3.3 V
|   falling waveform, R_fixture 50.000, V_fixture 3.300: 20-80 % time 133ps typ, 203ps min, 85.4ps max; typ from 3.3 V to 0.671 V
|   falling waveform, R_fixture 50.000, V_fixture 0.0: 20-80 % time 92.1ps typ, 149ps min, 60.5ps max; typ from 2.57 V to 0.001 V
[Pulldown]
|Voltage   I(typ)   I(min)   I(max)
-3.3V     -4.508A    -3.483A    -6.264A
-1.1V     -430.1mA   -440.6mA   -433.4mA
-1V       -282.5mA   -321.4mA   -261.4mA
-900mV    -168.1mA   -213.9mA   -168.3mA
-800mV    -102.3mA   -127.5mA   -140.7mA
-600mV    -61.63mA   -43.3mA    -90.26mA
-400mV    -36.69mA   -25.57mA   -53.1mA
1.2V      77.46mA    52.99mA    113.4mA
4.4V      124mA      94.74mA    167.8mA
5.2V      189.2mA    142.9mA    267.1mA
6V        290.4mA    212.5mA    428.2mA
6.6V      389.7mA    277.3mA    588.9mA
[Pullup]
|Voltage   I(typ)   I(min)   I(max)
-3.3V     373mA      275.3mA    580.2mA
400mV     -30.75mA   -22.93mA   -47.9mA
1.8V      -90.1mA    -64.69mA   -145.8mA
3.7V      -102mA     -75.7mA    -169.1mA
3.9V      -113.4mA   -143.5mA   -171.6mA
4.1V      -146.7mA   -338.7mA   -195.2mA
4.2V      -224.4mA   -457.7mA   -214.8mA
4.4V      -521mA     -713.3mA   -268.6mA
4.5V      -691.6mA   -845.9mA   -420.8mA
4.6V      -867.9mA   -980.3mA   -645.1mA
4.7V      -1.048A    -1.116A    -890.8mA
6.6V      -4.617A    -3.787A    -5.985A
[Ramp]
| variable   typ   min   max
dV/dt_r   1.541/0.128n   1.340/0.191n   1.776/74.183p
dV/dt_f   1.577/0.133n   1.344/0.203n   1.788/85.352p
R_load = 50.000
[Rising Waveform]
R_fixture= 50.000
V_fixture= 0.0
V_fixture_min= 0.0
V_fixture_max= 0.0
|time   V(typ)   V(min)   V(max)
0s        1.249mV    1.066mV    1.539mV
560ps     1.283mV    1.079mV    -42.6mV
709ps     1.239mV    1.079mV    2.644V
960ps     -1.897mV   1.168mV    2.9V
1.087ns   1.614V     1.228mV    2.925V
1.199ns   2.29V      943.5uV    2.937V
1.508ns   2.5V       -38.56mV   2.953V
1.803ns   2.538V     1.84V      2.959V
2.261ns   2.56V      2.168V     2.961V
20ns      2.569V     2.234V     2.962V
[Rising Waveform]
R_fixture= 50.000
V_fixture= 3.300
V_fixture_min= 3.140
V_fixture_max= 3.470
|time   V(typ)   V(min)   V(max)
0s        671.1mV    900.8mV    489.6mV
537ps     671.2mV    900.8mV    507.1mV
666ps     671.5mV    900.8mV    3.185V
923ps     1.095V     900.8mV    3.432V
1.077ns   2.997V     901.6mV    3.448V
1.313ns   3.251V     912.3mV    3.461V
1.424ns   3.267V     1.4V       3.464V
1.671ns   3.283V     2.929V     3.467V
1.998ns   3.293V     3.107V     3.469V
20ns      3.3V       3.14V      3.47V
[Falling Waveform]
R_fixture= 50.000
V_fixture= 3.300
V_fixture_min= 3.140
V_fixture_max= 3.470
|time   V(typ)   V(min)   V(max)
0s        3.3V       3.14V      3.47V
560ps     3.3V       3.14V      3.552V
711ps     3.3V       3.14V      875.6mV
956ps     3.393V     3.14V      535.4mV
1.012ns   2.957V     3.14V      525.4mV
1.19ns    1.025V     3.14V      507.3mV
1.581ns   705.6mV    3.238V     493.2mV
1.918ns   683.5mV    1.287V     490.9mV
2.313ns   675.2mV    949.6mV    489.8mV
20ns      671.1mV    900.8mV    489.5mV
[Falling Waveform]
R_fixture= 50.000
V_fixture= 0.0
V_fixture_min= 0.0
V_fixture_max= 0.0
|time   V(typ)   V(min)   V(max)
0s        2.569V     2.234V     2.962V
550ps     2.569V     2.234V     2.972V
666ps     2.569V     2.234V     332.2mV
906ps     2.571V     2.234V     36.11mV
1.093ns   328.6mV    2.234V     17.18mV
1.343ns   39.15mV    2.232V     7.276mV
1.536ns   20.77mV    2.098V     4.196mV
1.778ns   10.11mV    260.5mV    2.727mV
2.079ns   4.798mV    34.25mV    1.986mV
20ns      1.249mV    1.066mV    1.538mV
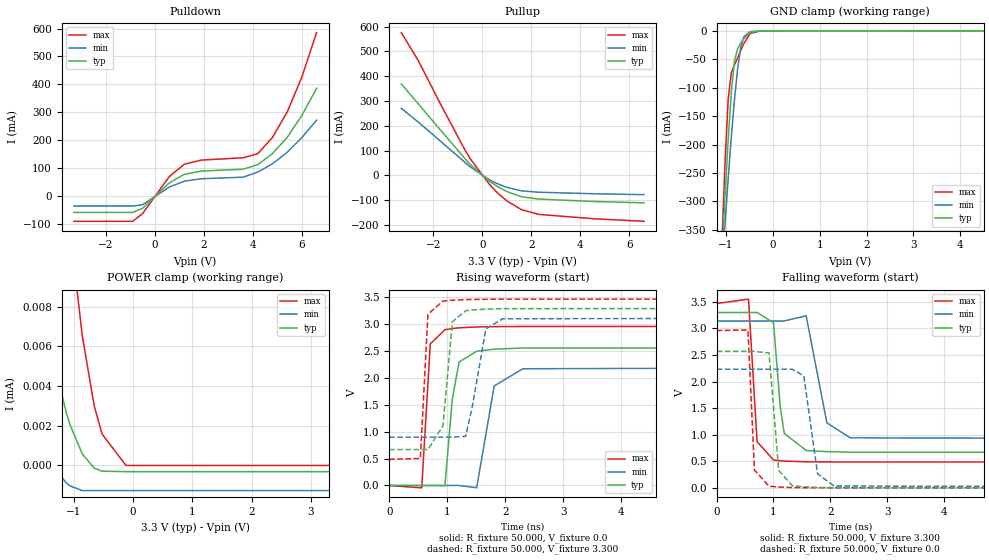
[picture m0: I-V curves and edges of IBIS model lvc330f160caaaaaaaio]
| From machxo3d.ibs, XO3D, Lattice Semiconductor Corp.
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|   Model lvc330f160caaaaaaaio
[Model] lvc330f160caaaaaaaio
Model_type I/O
Polarity   Non-Inverting
Enable   Active-Low
Vinl =  0.800V
Vinh =  2.000V
Vmeas =  1.650V
Cref =  0.0F
Rref =  1.000M
Vref =  0.0V
C_comp   4.200pF   3.800pF   7.500pF
[Temperature Range]   25.000   0.105k   -40.000
[Voltage Range]   3.300V   3.140V   3.470V
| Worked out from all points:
|   slope of the pulldown table from 0 to 0.495 V, typ, clamps not added: 12.2 ohm
|   slope of the pullup table from 0 to 0.495 V, typ, clamps not added: 13.4 ohm
|   GND clamp passes 1 mA (typ) near -0.43 V on its own axis
|   rising waveform, R_fixture 50.000, V_fixture 0.0: 20-80 % time 129ps typ, 192ps min, 74.4ps max; typ from 0 V to 2.57 V
|   rising waveform, R_fixture 50.000, V_fixture 3.300: 20-80 % time 113ps typ, 192ps min, 61.2ps max; typ from 0.668 V to 3.3 V
|   falling waveform, R_fixture 50.000, V_fixture 3.300: 20-80 % time 133ps typ, 204ps min, 85.2ps max; typ from 3.3 V to 0.668 V
|   falling waveform, R_fixture 50.000, V_fixture 0.0: 20-80 % time 92ps typ, 149ps min, 60.2ps max; typ from 2.57 V to 0 V
[Pulldown]
|Voltage   I(typ)   I(min)   I(max)
-3.3V     -58.64mA   -35.81mA   -90.41mA
-900mV    -58.64mA   -35.81mA   -90.41mA
-500mV    -44.08mA   -31.23mA   -63.19mA
600mV     47.81mA    32.63mA    70.46mA
1.2V      77.59mA    53.08mA    113.6mA
1.9V      89.57mA    62.04mA    128.9mA
3.6V      96.17mA    67.67mA    137.1mA
4.2V      112.5mA    85.73mA    151.6mA
4.8V      152.1mA    115.6mA    210mA
5.4V      210.2mA    156.8mA    300.8mA
6V        288.7mA    209.8mA    426.9mA
6.6V      386.1mA    271.9mA    585.6mA
[Pullup]
|Voltage   I(typ)   I(min)   I(max)
-3.3V     369.1mA    270.6mA    576.1mA
-2.6V     287.7mA    214.4mA    461.4mA
-1.7V     182.6mA    138mA      287.3mA
-700mV    67.48mA    52.18mA    101.9mA
-500mV    45.28mA    35.18mA    68.45mA
300mV     -23.64mA   -17.66mA   -36.76mA
600mV     -43.66mA   -32.42mA   -68.28mA
1V        -64.93mA   -47.78mA   -102.5mA
1.6V      -85.8mA    -62.05mA   -137.8mA
2.3V      -95.3mA    -67.57mA   -156.9mA
4.6V      -105.1mA   -73.89mA   -174.8mA
6.6V      -110.4mA   -77.4mA    -184.8mA
[GND_clamp]
|Voltage   I(typ)   I(min)   I(max)
-3.3V     -4.507A    -3.482A    -6.263A
-1.089V   -398.4mA   -420.6mA   -374.7mA
-1.022V   -290.7mA   -338.6mA   -230.6mA
-955mV    -191.4mA   -260.2mA   -120.1mA
-888mV    -107.5mA   -187mA     -73.7mA
-821mV    -53mA      -121.4mA   -59.85mA
-754mV    -31.41mA   -66.94mA   -47.47mA
-687mV    -21.17mA   -28.82mA   -34.25mA
-620mV    -13.21mA   -10.23mA   -22mA
-486mV    -2.63mA    -1.112mA   -4.479mA
-285mV    -80.91uA   -42.41uA   -152.3uA
6.6V      121.2uA    55.82uA    291.2uA
[POWER_clamp]
|Voltage   I(typ)   I(min)   I(max)
-3.3V     704.7uA    440.9uA    1.167mA
-2.596V   46.79uA    12.42uA    184.2uA
-2.328V   25.67uA    8.107uA    76.87uA
-1.792V   13.09uA    2.762uA    43.68uA
-1.39V    5.98uA     124nA      24.26uA
-1.122V   2.656uA    -886.2nA   13.98uA
-1.055V   2.02uA     -1.042uA   11.84uA
-854mV    585.7nA    -1.267uA   6.557uA
-653mV    -133.8nA   -1.267uA   3.017uA
-519mV    -290.6nA   -1.267uA   1.58uA
-117mV    -313.6nA   -1.267uA   0A
3.3V      -313.6nA   -1.267uA   0A
[Ramp]
| variable   typ   min   max
dV/dt_r   1.540/0.128n   1.339/0.192n   1.776/74.325p
dV/dt_f   1.578/0.133n   1.345/0.203n   1.789/85.067p
R_load = 50.000
[Rising Waveform]
R_fixture= 50.000
V_fixture= 0.0
V_fixture_min= 0.0
V_fixture_max= 0.0
|time   V(typ)   V(min)   V(max)
0s        10.33nV    27.72nV    115.7nV
560ps     34.94uV    15.35uV    -44.55mV
708ps     -1.107uV   15.35uV    2.635V
960ps     -4.34mV    101.3uV    2.899V
1.087ns   1.609V     171uV      2.921V
1.204ns   2.298V     -308.4uV   2.934V
1.507ns   2.498V     -42.74mV   2.95V
1.808ns   2.537V     1.851V     2.956V
2.3ns     2.558V     2.172V     2.959V
20ns      2.567V     2.232V     2.959V
[Rising Waveform]
R_fixture= 50.000
V_fixture= 3.300
V_fixture_min= 3.140
V_fixture_max= 3.470
|time   V(typ)   V(min)   V(max)
0s        668.3mV    898.5mV    486.2mV
537ps     668.3mV    898.5mV    502.9mV
667ps     668.7mV    898.5mV    3.187V
925ps     1.11V      898.5mV    3.431V
1.089ns   3.046V     899.5mV    3.448V
1.316ns   3.251V     913.6mV    3.459V
1.431ns   3.266V     1.465V     3.462V
1.665ns   3.282V     2.914V     3.465V
1.953ns   3.291V     3.102V     3.467V
20ns      3.299V     3.14V      3.468V
[Falling Waveform]
R_fixture= 50.000
V_fixture= 3.300
V_fixture_min= 3.140
V_fixture_max= 3.470
|time   V(typ)   V(min)   V(max)
0s        3.299V     3.14V      3.468V
560ps     3.299V     3.139V     3.55V
711ps     3.299V     3.14V      868.7mV
1ns       3.107V     3.14V      524.1mV
1.119ns   1.523V     3.139V     509.4mV
1.189ns   1.024V     3.14V      503.8mV
1.575ns   703.2mV    3.236V     489.9mV
1.94ns    680.7mV    1.222V     487.1mV
2.351ns   671.6mV    941.5mV    486.3mV
20ns      668.3mV    898.5mV    485.9mV
[Falling Waveform]
R_fixture= 50.000
V_fixture= 0.0
V_fixture_min= 0.0
V_fixture_max= 0.0
|time   V(typ)   V(min)   V(max)
0s        2.567V     2.232V     2.959V
550ps     2.567V     2.232V     2.969V
665ps     2.566V     2.232V     335.1mV
921ps     2.539V     2.232V     32.22mV
1.092ns   330mV      2.232V     15.42mV
1.332ns   39.22mV    2.231V     5.764mV
1.534ns   20.13mV    2.105V     2.675mV
1.776ns   8.715mV    263.5mV    1.185mV
2.068ns   3.535mV    34.32mV    436.5uV
20ns      -9.294nV   16.02nV    85.91nV
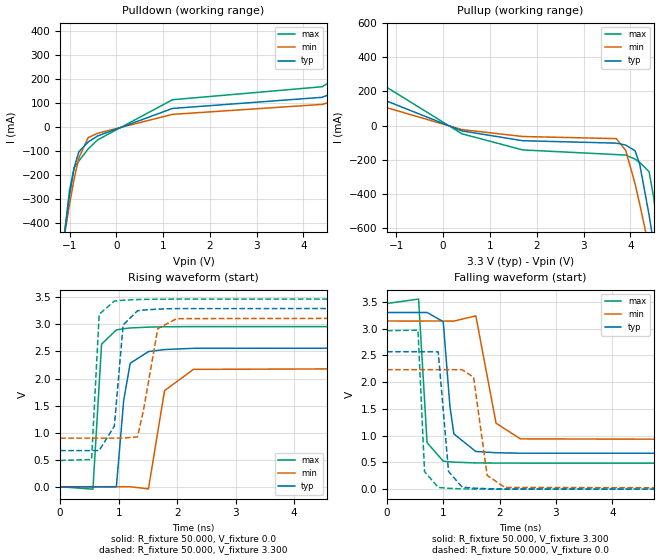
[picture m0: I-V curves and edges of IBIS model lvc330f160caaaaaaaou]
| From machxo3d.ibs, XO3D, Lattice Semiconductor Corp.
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|   Model lvc330f160caaaaaaaou
[Model] lvc330f160caaaaaaaou
Model_type Output
Polarity   Non-Inverting
Enable   Active-High
Vmeas =  1.650V
Cref =  0.0F
Rref =  1.000M
Vref =  0.0V
C_comp   4.200pF   3.800pF   7.500pF
[Temperature Range]   25.000   0.105k   -40.000
[Voltage Range]   3.300V   3.140V   3.470V
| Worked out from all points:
|   slope of the pulldown table from 0 to 0.495 V, typ, clamps not added: 12.1 ohm
|   slope of the pullup table from 0 to 0.495 V, typ, clamps not added: 13.4 ohm
|   rising waveform, R_fixture 50.000, V_fixture 0.0: 20-80 % time 129ps typ, 192ps min, 74.4ps max; typ from 0 V to 2.57 V
|   rising waveform, R_fixture 50.000, V_fixture 3.300: 20-80 % time 113ps typ, 192ps min, 61.2ps max; typ from 0.668 V to 3.3 V
|   falling waveform, R_fixture 50.000, V_fixture 3.300: 20-80 % time 133ps typ, 204ps min, 85.2ps max; typ from 3.3 V to 0.668 V
|   falling waveform, R_fixture 50.000, V_fixture 0.0: 20-80 % time 91.8ps typ, 149ps min, 60.3ps max; typ from 2.57 V to 0 V
[Pulldown]
|Voltage   I(typ)   I(min)   I(max)
-3.3V     -4.508A    -3.483A    -6.264A
-1.1V     -430mA     -440.6mA   -433.4mA
-1V       -282.5mA   -321.4mA   -261.4mA
-900mV    -168.1mA   -213.9mA   -168.3mA
-800mV    -102.2mA   -127.5mA   -140.7mA
-600mV    -61.61mA   -43.29mA   -90.23mA
-400mV    -36.65mA   -25.53mA   -53.02mA
1.2V      77.69mA    53.11mA    113.9mA
4.4V      124mA      94.5mA     167.9mA
5.1V      178.8mA    134.8mA    251.3mA
6V        288.9mA    209.9mA    427.3mA
6.6V      386.9mA    272.6mA    586.8mA
[Pullup]
|Voltage   I(typ)   I(min)   I(max)
-3.3V     369.9mA    271.1mA    577.6mA
400mV     -30.61mA   -22.86mA   -47.59mA
1.7V      -87.95mA   -63.42mA   -141.7mA
3.7V      -102mA     -75.68mA   -168.9mA
3.9V      -113.4mA   -143.5mA   -171.5mA
4.1V      -146.7mA   -338.7mA   -195.2mA
4.2V      -224.4mA   -457.7mA   -214.8mA
4.4V      -521mA     -713.3mA   -268.6mA
4.5V      -691.6mA   -845.9mA   -420.8mA
4.6V      -867.9mA   -980.3mA   -645.1mA
4.7V      -1.048A    -1.116A    -890.7mA
6.6V      -4.617A    -3.787A    -5.985A
[Ramp]
| variable   typ   min   max
dV/dt_r   1.540/0.128n   1.339/0.192n   1.776/74.316p
dV/dt_f   1.578/0.133n   1.345/0.203n   1.789/85.064p
R_load = 50.000
[Rising Waveform]
R_fixture= 50.000
V_fixture= 0.0
V_fixture_min= 0.0
V_fixture_max= 0.0
|time   V(typ)   V(min)   V(max)
0s        10.33nV    27.72nV    115.7nV
560ps     35.12uV    14.58uV    -44.54mV
708ps     -7.986uV   14.58uV    2.635V
961ps     826.9uV    100.2uV    2.898V
1.086ns   1.597V     168.5uV    2.921V
1.197ns   2.282V     -61.99uV   2.934V
1.509ns   2.498V     -38.65mV   2.95V
1.784ns   2.535V     1.776V     2.956V
2.279ns   2.558V     2.169V     2.959V
20ns      2.567V     2.232V     2.959V
[Rising Waveform]
R_fixture= 50.000
V_fixture= 3.300
V_fixture_min= 3.140
V_fixture_max= 3.470
|time   V(typ)   V(min)   V(max)
0s        668.3mV    898.5mV    486.2mV
537ps     668.3mV    898.5mV    502.9mV
667ps     668.7mV    898.5mV    3.187V
926ps     1.12V      898.5mV    3.431V
1.076ns   2.989V     899.4mV    3.447V
1.321ns   3.252V     920.5mV    3.459V
1.425ns   3.266V     1.419V     3.462V
1.668ns   3.282V     2.921V     3.465V
1.991ns   3.292V     3.106V     3.467V
20ns      3.299V     3.14V      3.468V
[Falling Waveform]
R_fixture= 50.000
V_fixture= 3.300
V_fixture_min= 3.140
V_fixture_max= 3.470
|time   V(typ)   V(min)   V(max)
0s        3.299V     3.14V      3.468V
560ps     3.299V     3.139V     3.55V
711ps     3.299V     3.14V      868.6mV
998ps     3.129V     3.14V      523.9mV
1.118ns   1.533V     3.139V     509.5mV
1.187ns   1.032V     3.139V     504.5mV
1.577ns   703mV      3.236V     489.8mV
1.936ns   680.5mV    1.232V     487mV
2.368ns   671.6mV    939.3mV    486.2mV
20ns      668.3mV    898.5mV    485.9mV
[Falling Waveform]
R_fixture= 50.000
V_fixture= 0.0
V_fixture_min= 0.0
V_fixture_max= 0.0
|time   V(typ)   V(min)   V(max)
0s        2.567V     2.232V     2.959V
550ps     2.567V     2.232V     2.969V
666ps     2.566V     2.232V     326.9mV
909ps     2.564V     2.232V     33.46mV
1.092ns   330.1mV    2.232V     15.71mV
1.333ns   39.02mV    2.231V     5.792mV
1.537ns   19.52mV    2.091V     2.676mV
1.778ns   8.683mV    257.5mV    1.197mV
2.092ns   3.366mV    31.32mV    331.1uV
20ns      -241.2nV   -58.9nV    -169.5nV
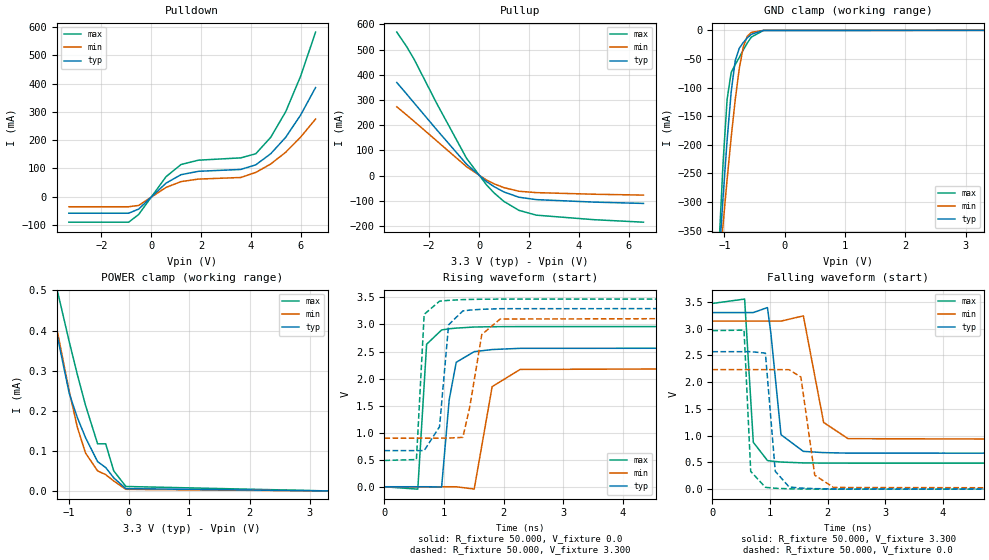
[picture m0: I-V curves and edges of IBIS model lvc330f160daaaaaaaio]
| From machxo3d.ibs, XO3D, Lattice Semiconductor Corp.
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|   Model lvc330f160daaaaaaaio
[Model] lvc330f160daaaaaaaio
Model_type I/O
Polarity   Non-Inverting
Enable   Active-Low
Vinl =  0.800V
Vinh =  2.000V
Vmeas =  1.650V
Cref =  0.0F
Rref =  1.000M
Vref =  0.0V
C_comp   4.200pF   3.800pF   7.500pF
[Temperature Range]   25.000   0.105k   -40.000
[Voltage Range]   3.300V   3.140V   3.470V
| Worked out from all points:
|   slope of the pulldown table from 0 to 0.495 V, typ, clamps not added: 12.2 ohm
|   slope of the pullup table from 0 to 0.495 V, typ, clamps not added: 13.4 ohm
|   GND clamp passes 1 mA (typ) near -0.43 V on its own axis
|   POWER clamp passes 1 mA (typ) near -1.85 V on its own axis
|   rising waveform, R_fixture 50.000, V_fixture 0.0: 20-80 % time 129ps typ, 192ps min, 74.6ps max; typ from 0 V to 2.57 V
|   rising waveform, R_fixture 50.000, V_fixture 3.300: 20-80 % time 113ps typ, 192ps min, 61.3ps max; typ from 0.668 V to 3.3 V
|   falling waveform, R_fixture 50.000, V_fixture 3.300: 20-80 % time 134ps typ, 205ps min, 85.6ps max; typ from 3.3 V to 0.668 V
|   falling waveform, R_fixture 50.000, V_fixture 0.0: 20-80 % time 92.3ps typ, 149ps min, 60.5ps max; typ from 2.57 V to 0 V
[Pulldown]
|Voltage   I(typ)   I(min)   I(max)
-3.3V     -58.64mA   -35.81mA   -90.41mA
-900mV    -58.64mA   -35.81mA   -90.41mA
-500mV    -44.08mA   -31.23mA   -63.19mA
600mV     47.81mA    32.63mA    70.46mA
1.2V      77.59mA    53.08mA    113.6mA
1.9V      89.57mA    62.04mA    128.9mA
3.6V      96.17mA    67.67mA    137.1mA
4.2V      112.4mA    85.6mA     151.6mA
4.8V      151.7mA    115.4mA    209.7mA
5.4V      209.7mA    156.9mA    300.1mA
6V        288.5mA    210.5mA    426mA
6.6V      385.8mA    274.4mA    581.9mA
[Pullup]
|Voltage   I(typ)   I(min)   I(max)
-3.3V     369.2mA    272.8mA    569.1mA
-2.9V     323mA      240mA      510.9mA
-2.6V     287.6mA    214.8mA    460.5mA
-1.7V     182.2mA    137.9mA    286.7mA
-500mV    45.28mA    35.17mA    68.49mA
300mV     -23.64mA   -17.66mA   -36.76mA
600mV     -43.66mA   -32.42mA   -68.28mA
1V        -64.93mA   -47.78mA   -102.5mA
1.6V      -85.8mA    -62.05mA   -137.8mA
2.3V      -95.3mA    -67.57mA   -156.9mA
4.6V      -105.1mA   -73.89mA   -174.8mA
6.6V      -110.4mA   -77.4mA    -184.8mA
[GND_clamp]
|Voltage   I(typ)   I(min)   I(max)
-3.3V     -4.507A    -3.482A    -6.263A
-1.089V   -398.4mA   -420.6mA   -374.7mA
-1.022V   -290.7mA   -338.6mA   -230.6mA
-955mV    -191.4mA   -260.2mA   -120.1mA
-888mV    -107.5mA   -187mA     -73.7mA
-821mV    -53mA      -121.4mA   -59.85mA
-754mV    -31.41mA   -66.94mA   -47.47mA
-687mV    -21.17mA   -28.82mA   -34.25mA
-620mV    -13.21mA   -10.23mA   -22mA
-553mV    -6.875mA   -3.578mA   -11.73mA
-352mV    -176.3uA   -89.98uA   -279uA
3.3V      50.87nA    0A         -26.43uA
[POWER_clamp]
|Voltage   I(typ)   I(min)   I(max)
-3.3V     3.967mA    2.512mA    11.53mA
-1.323V   507.3uA    506.4uA    605.6uA
-1.256V   446.6uA    452.8uA    548.7uA
-1.189V   387.7uA    399.8uA    501.1uA
-988mV    242.5uA    247.5uA    371.4uA
-854mV    182.6uA    158.2uA    289.7uA
-720mV    133.1uA    94.82uA    213.9uA
-519mV    73.06uA    49.89uA    117.5uA
-385mV    58.36uA    40.66uA    117.5uA
-251mV    32.53uA    24.74uA    49.87uA
-50mV     5.761uA    3.987uA    11.09uA
3.3V      0A         0A         0A
[Ramp]
| variable   typ   min   max
dV/dt_r   1.541/0.128n   1.340/0.192n   1.777/74.489p
dV/dt_f   1.579/0.133n   1.345/0.204n   1.790/85.539p
R_load = 50.000
[Rising Waveform]
R_fixture= 50.000
V_fixture= 0.0
V_fixture_min= 0.0
V_fixture_max= 0.0
|time   V(typ)   V(min)   V(max)
0s        10.33nV    27.72nV    115.7nV
560ps     34.94uV    15.34uV    -44.55mV
708ps     -1.108uV   15.34uV    2.635V
960ps     -4.339mV   101.3uV    2.899V
1.087ns   1.609V     171uV      2.921V
1.205ns   2.301V     -308.4uV   2.933V
1.507ns   2.498V     -42.74mV   2.953V
1.808ns   2.537V     1.851V     2.959V
2.278ns   2.559V     2.169V     2.961V
20ns      2.569V     2.234V     2.962V
[Rising Waveform]
R_fixture= 50.000
V_fixture= 3.300
V_fixture_min= 3.140
V_fixture_max= 3.470
|time   V(typ)   V(min)   V(max)
0s        668.3mV    898.5mV    486.2mV
537ps     668.3mV    898.5mV    502.9mV
667ps     668.7mV    898.5mV    3.187V
925ps     1.11V      898.5mV    3.431V
1.077ns   2.994V     899.4mV    3.446V
1.316ns   3.251V     913.6mV    3.46V
1.431ns   3.266V     1.465V     3.463V
1.634ns   3.281V     2.814V     3.467V
1.944ns   3.292V     3.101V     3.469V
20ns      3.3V       3.14V      3.47V
[Falling Waveform]
R_fixture= 50.000
V_fixture= 3.300
V_fixture_min= 3.140
V_fixture_max= 3.470
|time   V(typ)   V(min)   V(max)
0s        3.3V       3.14V      3.47V
560ps     3.3V       3.14V      3.552V
711ps     3.3V       3.14V      875.6mV
956ps     3.393V     3.14V      535.6mV
1.014ns   2.93V      3.14V      525.6mV
1.192ns   1.017V     3.14V      506.8mV
1.58ns    705.7mV    3.238V     490.8mV
1.932ns   683.1mV    1.247V     487.2mV
2.356ns   673.2mV    943.4mV    486.2mV
20ns      668.2mV    898.5mV    486.2mV
[Falling Waveform]
R_fixture= 50.000
V_fixture= 0.0
V_fixture_min= 0.0
V_fixture_max= 0.0
|time   V(typ)   V(min)   V(max)
0s        2.569V     2.234V     2.962V
550ps     2.569V     2.234V     2.972V
666ps     2.569V     2.234V     332.2mV
921ps     2.542V     2.234V     34.25mV
1.092ns   334.3mV    2.234V     17.11mV
1.333ns   40.88mV    2.232V     6.751mV
1.537ns   20.28mV    2.094V     3.056mV
1.778ns   10.01mV    260.5mV    1.256mV
2.105ns   3.904mV    31.22mV    361.3uV
20ns      -32.38nV   58.65nV    4.344nV
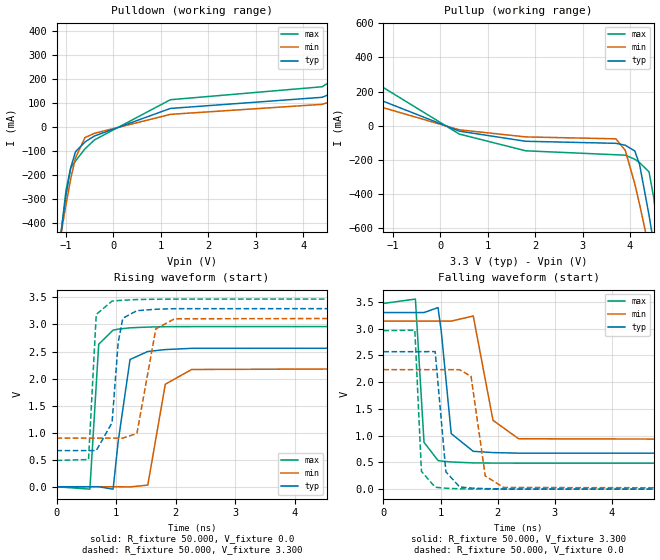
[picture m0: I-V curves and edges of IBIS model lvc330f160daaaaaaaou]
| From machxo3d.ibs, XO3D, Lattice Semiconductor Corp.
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|   Model lvc330f160daaaaaaaou
[Model] lvc330f160daaaaaaaou
Model_type Output
Polarity   Non-Inverting
Enable   Active-High
Vmeas =  1.650V
Cref =  0.0F
Rref =  1.000M
Vref =  0.0V
C_comp   4.200pF   3.800pF   7.500pF
[Temperature Range]   25.000   0.105k   -40.000
[Voltage Range]   3.300V   3.140V   3.470V
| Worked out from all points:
|   slope of the pulldown table from 0 to 0.495 V, typ, clamps not added: 12.1 ohm
|   slope of the pullup table from 0 to 0.495 V, typ, clamps not added: 13.3 ohm
|   rising waveform, R_fixture 50.000, V_fixture 0.0: 20-80 % time 129ps typ, 192ps min, 74.6ps max; typ from 0 V to 2.57 V
|   rising waveform, R_fixture 50.000, V_fixture 3.300: 20-80 % time 112ps typ, 192ps min, 61.3ps max; typ from 0.668 V to 3.3 V
|   falling waveform, R_fixture 50.000, V_fixture 3.300: 20-80 % time 134ps typ, 204ps min, 85.6ps max; typ from 3.3 V to 0.668 V
|   falling waveform, R_fixture 50.000, V_fixture 0.0: 20-80 % time 92.2ps typ, 149ps min, 60.5ps max; typ from 2.57 V to 0 V
[Pulldown]
|Voltage   I(typ)   I(min)   I(max)
-3.3V     -4.508A    -3.483A    -6.264A
-1.1V     -430mA     -440.6mA   -433.4mA
-1V       -282.5mA   -321.4mA   -261.4mA
-900mV    -168.1mA   -213.9mA   -168.3mA
-800mV    -102.2mA   -127.5mA   -140.7mA
-600mV    -61.61mA   -43.29mA   -90.23mA
-400mV    -36.65mA   -25.53mA   -53.02mA
1.2V      77.69mA    53.11mA    113.9mA
4.4V      124mA      94.74mA    167.8mA
5.2V      189.2mA    142.9mA    267.1mA
6V        290.4mA    212.5mA    428.2mA
6.6V      389.7mA    277.3mA    588.9mA
[Pullup]
|Voltage   I(typ)   I(min)   I(max)
-3.3V     373mA      275.3mA    580.2mA
400mV     -30.75mA   -22.93mA   -47.9mA
1.8V      -90.1mA    -64.56mA   -145.8mA
3.7V      -102mA     -75.68mA   -168.9mA
3.9V      -113.4mA   -143.5mA   -171.5mA
4.1V      -146.7mA   -338.7mA   -195.2mA
4.2V      -224.4mA   -457.7mA   -214.8mA
4.4V      -521mA     -713.3mA   -268.6mA
4.5V      -691.6mA   -845.9mA   -420.8mA
4.6V      -867.9mA   -980.3mA   -645.1mA
4.7V      -1.048A    -1.116A    -890.7mA
6.6V      -4.617A    -3.787A    -5.985A
[Ramp]
| variable   typ   min   max
dV/dt_r   1.541/0.128n   1.340/0.192n   1.777/74.480p
dV/dt_f   1.579/0.133n   1.345/0.204n   1.790/85.538p
R_load = 50.000
[Rising Waveform]
R_fixture= 50.000
V_fixture= 0.0
V_fixture_min= 0.0
V_fixture_max= 0.0
|time   V(typ)   V(min)   V(max)
0s        10.33nV    27.72nV    115.7nV
560ps     35.1uV     14.56uV    -44.54mV
708ps     -7.985uV   14.56uV    2.635V
950ps     -44.83mV   100.2uV    2.896V
1.035ns   838.3mV    122.7uV    2.914V
1.234ns   2.353V     -3.143mV   2.938V
1.532ns   2.501V     30.79mV    2.952V
1.826ns   2.536V     1.896V     2.959V
2.269ns   2.559V     2.168V     2.961V
20ns      2.569V     2.234V     2.962V
[Rising Waveform]
R_fixture= 50.000
V_fixture= 3.300
V_fixture_min= 3.140
V_fixture_max= 3.470
|time   V(typ)   V(min)   V(max)
0s        668.3mV    898.5mV    486.2mV
537ps     668.3mV    898.5mV    502.9mV
667ps     668.7mV    898.5mV    3.187V
932ps     1.184V     898.5mV    3.432V
1.035ns   2.668V     898.9mV    3.443V
1.112ns   3.115V     899.5mV    3.448V
1.349ns   3.255V     982.9mV    3.461V
1.667ns   3.282V     2.919V     3.467V
1.981ns   3.292V     3.105V     3.469V
20ns      3.3V       3.14V      3.47V
[Falling Waveform]
R_fixture= 50.000
V_fixture= 3.300
V_fixture_min= 3.140
V_fixture_max= 3.470
|time   V(typ)   V(min)   V(max)
0s        3.3V       3.14V      3.47V
560ps     3.3V       3.14V      3.552V
711ps     3.3V       3.14V      875.6mV
956ps     3.393V     3.14V      535.4mV
1.012ns   2.957V     3.14V      525.4mV
1.187ns   1.038V     3.14V      507.8mV
1.573ns   706.7mV    3.235V     490.9mV
1.918ns   683.5mV    1.287V     487.2mV
2.366ns   673.1mV    942.2mV    486.2mV
20ns      668.3mV    898.5mV    486.1mV
[Falling Waveform]
R_fixture= 50.000
V_fixture= 0.0
V_fixture_min= 0.0
V_fixture_max= 0.0
|time   V(typ)   V(min)   V(max)
0s        2.569V     2.234V     2.962V
550ps     2.569V     2.234V     2.972V
666ps     2.569V     2.234V     332.2mV
906ps     2.571V     2.234V     36.11mV
1.094ns   323.1mV    2.234V     17.33mV
1.336ns   40.34mV    2.232V     6.718mV
1.534ns   20.77mV    2.107V     3.186mV
1.783ns   10.17mV    246.2mV    1.329mV
2.105ns   3.933mV    31.21mV    400.9uV
20ns      -71.35nV   53.47nV    44.83nV
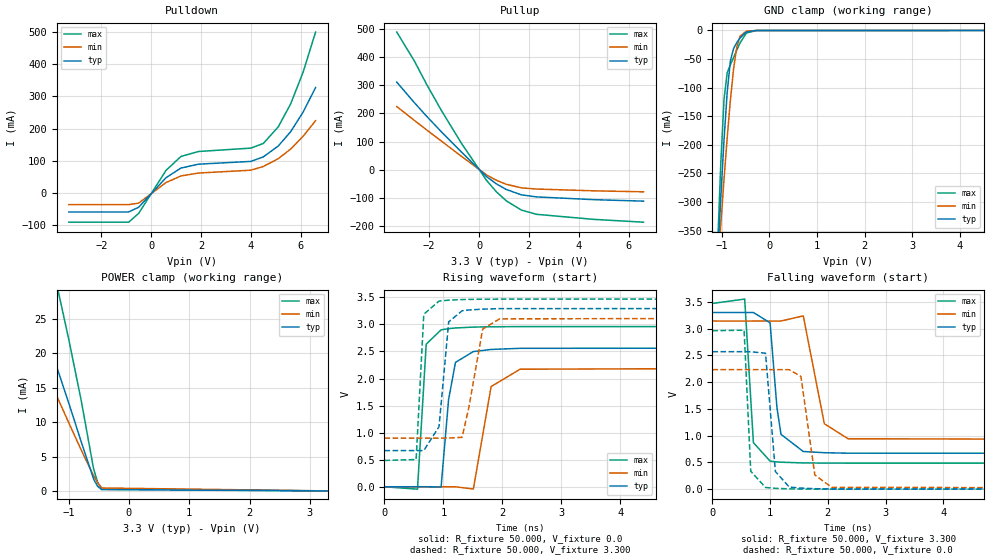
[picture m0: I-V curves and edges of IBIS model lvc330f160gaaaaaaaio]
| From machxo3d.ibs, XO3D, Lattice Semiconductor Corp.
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|   Model lvc330f160gaaaaaaaio
[Model] lvc330f160gaaaaaaaio
Model_type I/O
Polarity   Non-Inverting
Enable   Active-Low
Vinl =  0.800V
Vinh =  2.000V
Vmeas =  1.650V
Cref =  0.0F
Rref =  1.000M
Vref =  0.0V
C_comp   4.200pF   3.800pF   7.500pF
[Temperature Range]   25.000   0.105k   -40.000
[Voltage Range]   3.300V   3.140V   3.470V
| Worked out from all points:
|   slope of the pulldown table from 0 to 0.495 V, typ, clamps not added: 12.2 ohm
|   slope of the pullup table from 0 to 0.495 V, typ, clamps not added: 13.4 ohm
|   GND clamp passes 1 mA (typ) near -0.43 V on its own axis
|   POWER clamp passes 1 mA (typ) near -0.54 V on its own axis
|   rising waveform, R_fixture 50.000, V_fixture 0.0: 20-80 % time 129ps typ, 192ps min, 74.4ps max; typ from 0 V to 2.57 V
|   rising waveform, R_fixture 50.000, V_fixture 3.300: 20-80 % time 113ps typ, 192ps min, 61.2ps max; typ from 0.668 V to 3.3 V
|   falling waveform, R_fixture 50.000, V_fixture 3.300: 20-80 % time 133ps typ, 204ps min, 85.2ps max; typ from 3.3 V to 0.668 V
|   falling waveform, R_fixture 50.000, V_fixture 0.0: 20-80 % time 92ps typ, 149ps min, 60.2ps max; typ from 2.57 V to 0 V
[Pulldown]
|Voltage   I(typ)   I(min)   I(max)
-3.3V     -58.64mA   -35.81mA   -90.41mA
-900mV    -58.64mA   -35.81mA   -90.41mA
-500mV    -44.08mA   -31.23mA   -63.19mA
600mV     47.81mA    32.63mA    70.46mA
1.2V      77.59mA    53.08mA    113.6mA
1.9V      89.57mA    62.04mA    128.9mA
4V        98.19mA    70.91mA    139.4mA
4.5V      112.1mA    82.3mA     153.7mA
5.1V      145.8mA    106.5mA    205.1mA
5.6V      190.4mA    136.5mA    276.5mA
6.1V      251.2mA    176.2mA    375.1mA
6.6V      327.5mA    224.4mA    499.4mA
[Pullup]
|Voltage   I(typ)   I(min)   I(max)
-3.3V     310.5mA    224mA      487.4mA
-2.6V     238.5mA    175.5mA    386mA
-2.1V     189.6mA    141.5mA    302.2mA
-1.5V     133.8mA    101.2mA    208.7mA
-700mV    62.85mA    47.92mA    93.53mA
300mV     -23.64mA   -17.66mA   -36.76mA
700mV     -49.55mA   -36.72mA   -77.66mA
1.1V      -69.31mA   -50.87mA   -109.7mA
1.7V      -88.05mA   -63.45mA   -141.9mA
2.3V      -95.3mA    -67.57mA   -156.9mA
4.6V      -105.1mA   -73.89mA   -174.8mA
6.6V      -110.4mA   -77.4mA    -184.8mA
[GND_clamp]
|Voltage   I(typ)   I(min)   I(max)
-3.3V     -4.507A    -3.482A    -6.263A
-1.089V   -398.4mA   -420.6mA   -374.7mA
-1.022V   -290.7mA   -338.6mA   -230.6mA
-955mV    -191.4mA   -260.2mA   -120.1mA
-888mV    -107.5mA   -187mA     -73.7mA
-821mV    -53mA      -121.4mA   -59.85mA
-754mV    -31.41mA   -66.94mA   -47.47mA
-687mV    -21.17mA   -28.82mA   -34.25mA
-620mV    -13.21mA   -10.23mA   -22mA
-486mV    -2.63mA    -1.112mA   -4.479mA
-285mV    -80.91uA   -42.41uA   -152.3uA
6.6V      121.2uA    55.84uA    291.2uA
[POWER_clamp]
|Voltage   I(typ)   I(min)   I(max)
-3.3V     59.17mA    46.96mA    89.71mA
-1.993V   37.21mA    28.87mA    58.18mA
-1.926V   35.73mA    27.67mA    56.02mA
-1.591V   27.93mA    21.43mA    44.63mA
-1.189V   17.84mA    13.65mA    29.69mA
-1.122V   16.09mA    12.35mA    27.06mA
-988mV    12.53mA    9.74mA     21.66mA
-787mV    7.047mA    5.88mA     12.98mA
-586mV    1.736mA    2.238mA    3.233mA
-519mV    672uA      1.196mA    1.278mA
-452mV    189uA      428.3uA    309.6uA
3.3V      0A         0A         0A
[Ramp]
| variable   typ   min   max
dV/dt_r   1.540/0.128n   1.339/0.192n   1.776/74.325p
dV/dt_f   1.578/0.133n   1.345/0.203n   1.789/85.067p
R_load = 50.000
[Rising Waveform]
R_fixture= 50.000
V_fixture= 0.0
V_fixture_min= 0.0
V_fixture_max= 0.0
|time   V(typ)   V(min)   V(max)
0s        10.33nV    27.72nV    115.7nV
560ps     34.91uV    15.36uV    -44.55mV
708ps     -1.112uV   15.36uV    2.635V
960ps     -4.34mV    101.3uV    2.899V
1.087ns   1.609V     170.9uV    2.921V
1.204ns   2.298V     -308.4uV   2.934V
1.507ns   2.498V     -42.74mV   2.95V
1.808ns   2.537V     1.851V     2.956V
2.3ns     2.558V     2.172V     2.959V
20ns      2.567V     2.232V     2.959V
[Rising Waveform]
R_fixture= 50.000
V_fixture= 3.300
V_fixture_min= 3.140
V_fixture_max= 3.470
|time   V(typ)   V(min)   V(max)
0s        668.3mV    898.5mV    486.2mV
537ps     668.3mV    898.5mV    502.9mV
667ps     668.7mV    898.5mV    3.187V
925ps     1.11V      898.5mV    3.431V
1.089ns   3.046V     899.5mV    3.448V
1.316ns   3.251V     913.6mV    3.459V
1.431ns   3.266V     1.465V     3.462V
1.665ns   3.282V     2.914V     3.465V
1.953ns   3.291V     3.102V     3.467V
20ns      3.299V     3.14V      3.468V
[Falling Waveform]
R_fixture= 50.000
V_fixture= 3.300
V_fixture_min= 3.140
V_fixture_max= 3.470
|time   V(typ)   V(min)   V(max)
0s        3.299V     3.14V      3.468V
560ps     3.299V     3.139V     3.55V
711ps     3.299V     3.14V      868.7mV
1ns       3.107V     3.14V      524.1mV
1.119ns   1.523V     3.139V     509.4mV
1.189ns   1.024V     3.14V      503.8mV
1.575ns   703.2mV    3.236V     489.9mV
1.94ns    680.7mV    1.222V     487.1mV
2.351ns   671.6mV    941.5mV    486.3mV
20ns      668.3mV    898.5mV    485.9mV
[Falling Waveform]
R_fixture= 50.000
V_fixture= 0.0
V_fixture_min= 0.0
V_fixture_max= 0.0
|time   V(typ)   V(min)   V(max)
0s        2.567V     2.232V     2.959V
550ps     2.567V     2.232V     2.969V
665ps     2.566V     2.232V     335.1mV
921ps     2.539V     2.232V     32.22mV
1.092ns   330mV      2.232V     15.42mV
1.332ns   39.22mV    2.231V     5.764mV
1.534ns   20.13mV    2.105V     2.675mV
1.776ns   8.715mV    263.5mV    1.185mV
2.068ns   3.535mV    34.32mV    436.5uV
20ns      -9.294nV   16.02nV    85.91nV
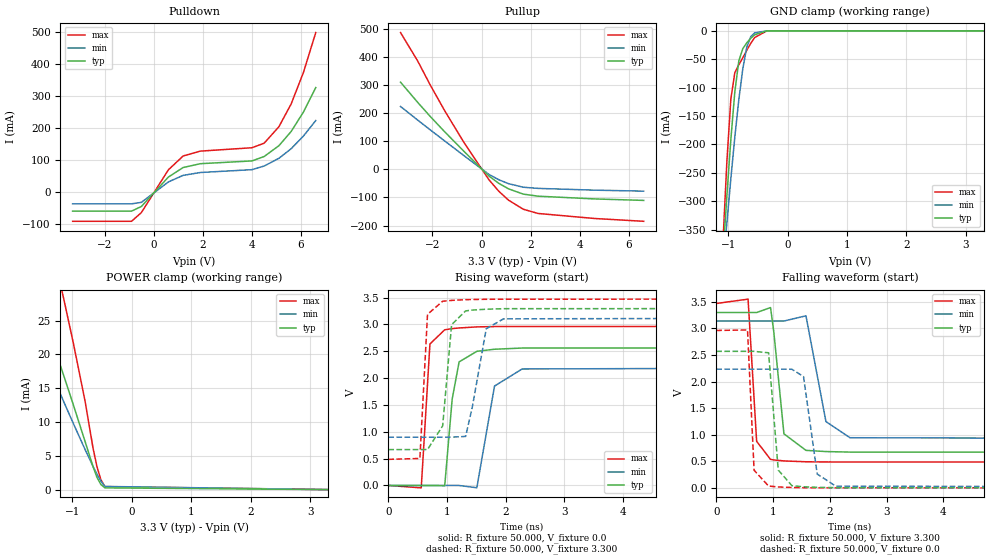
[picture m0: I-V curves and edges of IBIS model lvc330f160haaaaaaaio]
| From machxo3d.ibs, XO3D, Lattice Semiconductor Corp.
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|   Model lvc330f160haaaaaaaio
[Model] lvc330f160haaaaaaaio
Model_type I/O
Polarity   Non-Inverting
Enable   Active-Low
Vinl =  0.800V
Vinh =  2.000V
Vmeas =  1.650V
Cref =  0.0F
Rref =  1.000M
Vref =  0.0V
C_comp   4.200pF   3.800pF   7.500pF
[Temperature Range]   25.000   0.105k   -40.000
[Voltage Range]   3.300V   3.140V   3.470V
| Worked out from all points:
|   slope of the pulldown table from 0 to 0.495 V, typ, clamps not added: 12.2 ohm
|   slope of the pullup table from 0 to 0.495 V, typ, clamps not added: 13.4 ohm
|   GND clamp passes 1 mA (typ) near -0.43 V on its own axis
|   POWER clamp passes 1 mA (typ) near -0.53 V on its own axis
|   rising waveform, R_fixture 50.000, V_fixture 0.0: 20-80 % time 129ps typ, 192ps min, 74.6ps max; typ from 0 V to 2.57 V
|   rising waveform, R_fixture 50.000, V_fixture 3.300: 20-80 % time 113ps typ, 192ps min, 61.3ps max; typ from 0.668 V to 3.3 V
|   falling waveform, R_fixture 50.000, V_fixture 3.300: 20-80 % time 134ps typ, 205ps min, 85.6ps max; typ from 3.3 V to 0.668 V
|   falling waveform, R_fixture 50.000, V_fixture 0.0: 20-80 % time 92.3ps typ, 149ps min, 60.5ps max; typ from 2.57 V to 0 V
[Pulldown]
|Voltage   I(typ)   I(min)   I(max)
-3.3V     -58.64mA   -35.81mA   -90.41mA
-900mV    -58.64mA   -35.81mA   -90.41mA
-500mV    -44.08mA   -31.23mA   -63.19mA
600mV     47.81mA    32.63mA    70.46mA
1.2V      77.59mA    53.08mA    113.6mA
1.9V      89.57mA    62.04mA    128.9mA
4V        98.2mA     70.91mA    139.4mA
4.5V      112.1mA    82.3mA     153.7mA
5.1V      145.8mA    106.4mA    205.1mA
5.6V      190.4mA    136.5mA    276.5mA
6.1V      251.2mA    176.2mA    375.1mA
6.6V      327.5mA    224.4mA    499.3mA
[Pullup]
|Voltage   I(typ)   I(min)   I(max)
-3.3V     310.8mA    224.2mA    487.4mA
-2.6V     238.6mA    175.6mA    386mA
-2.1V     189.6mA    141.5mA    302.3mA
-1.5V     133.8mA    101.2mA    208.7mA
-700mV    62.85mA    47.92mA    93.52mA
300mV     -23.64mA   -17.66mA   -36.76mA
700mV     -49.55mA   -36.72mA   -77.66mA
1.1V      -69.31mA   -50.87mA   -109.7mA
1.7V      -88.05mA   -63.45mA   -141.9mA
2.3V      -95.3mA    -67.57mA   -156.9mA
4.6V      -105.1mA   -73.89mA   -174.8mA
6.6V      -110.4mA   -77.4mA    -184.8mA
[GND_clamp]
|Voltage   I(typ)   I(min)   I(max)
-3.3V     -4.507A    -3.482A    -6.263A
-1.089V   -398.4mA   -420.6mA   -374.7mA
-1.022V   -290.7mA   -338.6mA   -230.6mA
-955mV    -191.4mA   -260.2mA   -120.1mA
-888mV    -107.5mA   -187mA     -73.7mA
-821mV    -53mA      -121.4mA   -59.85mA
-754mV    -31.41mA   -66.94mA   -47.47mA
-687mV    -21.17mA   -28.82mA   -34.25mA
-620mV    -13.21mA   -10.23mA   -22mA
-553mV    -6.875mA   -3.578mA   -11.73mA
-352mV    -176.3uA   -89.98uA   -279uA
3.3V      50.87nA    0A         -26.43uA
[POWER_clamp]
|Voltage   I(typ)   I(min)   I(max)
-3.3V     62.1mA     51.02mA    92.7mA
-1.926V   36.35mA    28.59mA    56.55mA
-1.591V   28.28mA    21.98mA    45.01mA
-1.189V   18.03mA    13.9mA     29.96mA
-1.122V   16.26mA    12.55mA    27.31mA
-988mV    12.68mA    9.882mA    21.88mA
-787mV    7.154mA    5.963mA    13.15mA
-653mV    3.439mA    3.462mA    6.207mA
-586mV    1.819mA    2.29mA     3.395mA
-519mV    748.7uA    1.242mA    1.434mA
-452mV    255.4uA    468.1uA    442.9uA
3.3V      0A         0A         0A
[Ramp]
| variable   typ   min   max
dV/dt_r   1.541/0.128n   1.340/0.192n   1.777/74.489p
dV/dt_f   1.579/0.133n   1.345/0.204n   1.790/85.539p
R_load = 50.000
[Rising Waveform]
R_fixture= 50.000
V_fixture= 0.0
V_fixture_min= 0.0
V_fixture_max= 0.0
|time   V(typ)   V(min)   V(max)
0s        10.33nV    27.72nV    115.7nV
560ps     34.92uV    15.34uV    -44.55mV
708ps     -1.11uV    15.34uV    2.635V
960ps     -4.34mV    101.3uV    2.899V
1.087ns   1.609V     170.9uV    2.921V
1.205ns   2.301V     -308.4uV   2.933V
1.507ns   2.498V     -42.74mV   2.953V
1.808ns   2.537V     1.851V     2.959V
2.278ns   2.559V     2.169V     2.961V
20ns      2.569V     2.234V     2.962V
[Rising Waveform]
R_fixture= 50.000
V_fixture= 3.300
V_fixture_min= 3.140
V_fixture_max= 3.470
|time   V(typ)   V(min)   V(max)
0s        668.3mV    898.5mV    486.2mV
537ps     668.3mV    898.5mV    502.9mV
667ps     668.7mV    898.5mV    3.187V
925ps     1.11V      898.5mV    3.431V
1.077ns   2.994V     899.4mV    3.446V
1.316ns   3.251V     913.6mV    3.46V
1.431ns   3.266V     1.465V     3.463V
1.667ns   3.282V     2.919V     3.467V
1.962ns   3.292V     3.103V     3.469V
20ns      3.3V       3.14V      3.47V
[Falling Waveform]
R_fixture= 50.000
V_fixture= 3.300
V_fixture_min= 3.140
V_fixture_max= 3.470
|time   V(typ)   V(min)   V(max)
0s        3.3V       3.14V      3.47V
560ps     3.3V       3.14V      3.552V
711ps     3.3V       3.14V      875.6mV
956ps     3.393V     3.14V      535.6mV
1.014ns   2.93V      3.14V      525.6mV
1.192ns   1.017V     3.14V      506.8mV
1.58ns    705.7mV    3.238V     490.8mV
1.932ns   683.1mV    1.247V     487.2mV
2.356ns   673.2mV    943.4mV    486.2mV
20ns      668.2mV    898.5mV    486.2mV
[Falling Waveform]
R_fixture= 50.000
V_fixture= 0.0
V_fixture_min= 0.0
V_fixture_max= 0.0
|time   V(typ)   V(min)   V(max)
0s        2.569V     2.234V     2.962V
550ps     2.569V     2.234V     2.972V
666ps     2.569V     2.234V     332.2mV
921ps     2.542V     2.234V     34.25mV
1.092ns   334.3mV    2.234V     17.11mV
1.333ns   40.88mV    2.232V     6.751mV
1.537ns   20.28mV    2.094V     3.056mV
1.778ns   10.01mV    260.5mV    1.256mV
2.105ns   3.904mV    31.22mV    361.3uV
20ns      -32.38nV   58.65nV    4.344nV
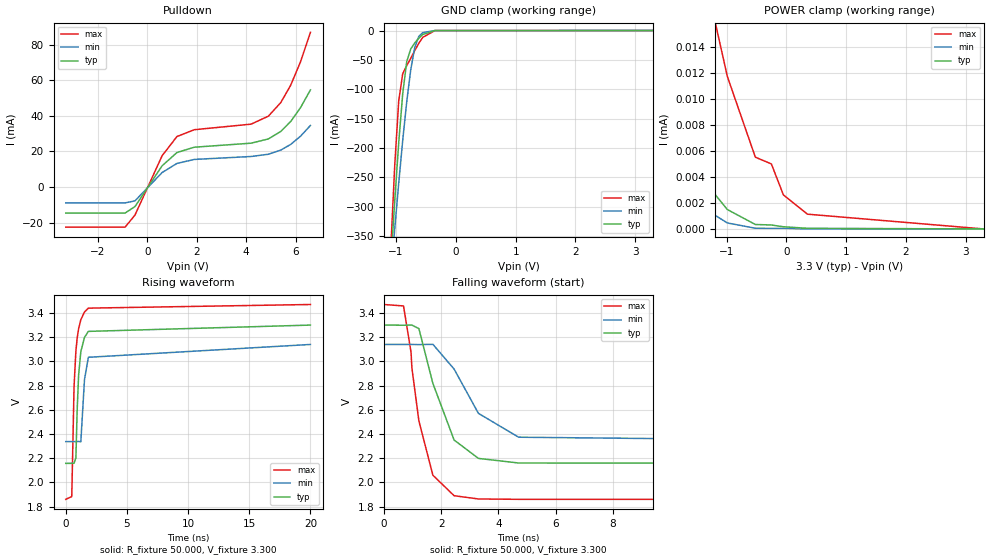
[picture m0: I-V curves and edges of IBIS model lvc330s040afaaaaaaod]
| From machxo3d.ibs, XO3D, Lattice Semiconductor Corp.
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|   Model lvc330s040afaaaaaaod
[Model] lvc330s040afaaaaaaod
Model_type I/O_open_drain
Polarity   Non-Inverting
Enable   Active-Low
Vinl =  0.800V
Vinh =  2.000V
Vmeas =  1.650V
Cref =  0.0F
Rref = 10.00k
Vref = 3.30V
C_comp   4.200pF   3.800pF   7.500pF
[Temperature Range]   25.000   0.105k   -40.000
[Voltage Range]   3.300V   3.140V   3.470V
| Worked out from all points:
|   slope of the pulldown table from 0 to 0.495 V, typ, clamps not added: 48.6 ohm
|   GND clamp passes 1 mA (typ) near -0.43 V on its own axis
|   rising waveform, R_fixture 50.000, V_fixture 3.300: 20-80 % time 337ps typ, 341ps min, 336ps max; typ from 2.16 V to 3.3 V
|   falling waveform, R_fixture 50.000, V_fixture 3.300: 20-80 % time 895ps typ, 1.23ns min, 635ps max; typ from 3.3 V to 2.16 V
[Pulldown]
|Voltage   I(typ)   I(min)   I(max)
-3.3V     -14.66mA   -8.951mA   -22.6mA
-900mV    -14.66mA   -8.951mA   -22.6mA
-500mV    -11.02mA   -7.807mA   -15.8mA
600mV     11.95mA    8.157mA    17.61mA
1.2V      19.4mA     13.27mA    28.41mA
1.9V      22.39mA    15.51mA    32.23mA
4.2V      24.66mA    17.16mA    35.37mA
4.9V      27.05mA    18.44mA    39.88mA
5.4V      31.26mA    20.77mA    47.51mA
5.8V      36.84mA    23.96mA    57.23mA
6.2V      44.67mA    28.59mA    70.48mA
6.6V      54.65mA    34.63mA    87.04mA
[GND_clamp]
|Voltage   I(typ)   I(min)   I(max)
-3.3V     -4.507A    -3.482A    -6.263A
-1.089V   -398.4mA   -420.6mA   -374.7mA
-1.022V   -290.7mA   -338.6mA   -230.6mA
-955mV    -191.3mA   -260.2mA   -120mA
-888mV    -107.5mA   -187mA     -73.64mA
-821mV    -52.96mA   -121.4mA   -59.79mA
-754mV    -31.36mA   -66.92mA   -47.4mA
-687mV    -21.12mA   -28.79mA   -34.18mA
-620mV    -13.16mA   -10.19mA   -21.93mA
-553mV    -6.814mA   -3.53mA    -11.64mA
-352mV    -96.36uA   -46.21uA   -149.8uA
3.3V      0A         0A         0A
[POWER_clamp]
|Voltage   I(typ)   I(min)   I(max)
-3.3V     732.2uA    455.9uA    1.265mA
-2.663V   69.44uA    15.46uA    306.8uA
-2.529V   27.69uA    10.95uA    164.1uA
-2.328V   15.69uA    8.498uA    64.68uA
-1.725V   7.348uA    3.693uA    30.69uA
-1.189V   2.632uA    1.04uA     15.85uA
-988mV    1.494uA    463.1nA    11.72uA
-519mV    342.8nA    54.78nA    5.51uA
-251mV    305.1nA    47.65nA    4.994uA
-50mV     169nA      47.65nA    2.616uA
352mV     50.67nA    4.149nA    1.135uA
3.3V      0A         0A         0A
[Ramp]
| variable   typ   min   max
dV/dt_r   0.685/0.336n   0.481/0.341n   0.965/0.335n
dV/dt_f   0.685/0.897n   0.481/1.234n   0.965/0.637n
R_load = 50.000
[Rising Waveform]
R_fixture= 50.000
V_fixture= 3.300
V_fixture_min= 3.140
V_fixture_max= 3.470
|time   V(typ)   V(min)   V(max)
0s        2.158V     2.338V     1.861V
491ps     2.158V     2.338V     1.884V
678ps     2.159V     2.338V     2.793V
828ps     2.203V     2.338V     3.085V
933ps     2.599V     2.338V     3.192V
1.051ns   2.888V     2.339V     3.27V
1.231ns   3.08V      2.336V     3.344V
1.53ns    3.198V     2.849V     3.408V
1.847ns   3.248V     3.034V     3.44V
20ns      3.3V       3.14V      3.47V
[Falling Waveform]
R_fixture= 50.000
V_fixture= 3.300
V_fixture_min= 3.140
V_fixture_max= 3.470
|time   V(typ)   V(min)   V(max)
0s        3.3V       3.14V      3.47V
680ps     3.299V     3.14V      3.458V
943ps     3.3V       3.14V      3.076V
973ps     3.3V       3.14V      2.946V
1.217ns   3.271V     3.139V     2.509V
1.707ns   2.818V     3.141V     2.06V
2.448ns   2.351V     2.937V     1.891V
3.299ns   2.199V     2.571V     1.864V
4.705ns   2.161V     2.374V     1.861V
20ns      2.158V     2.338V     1.861V
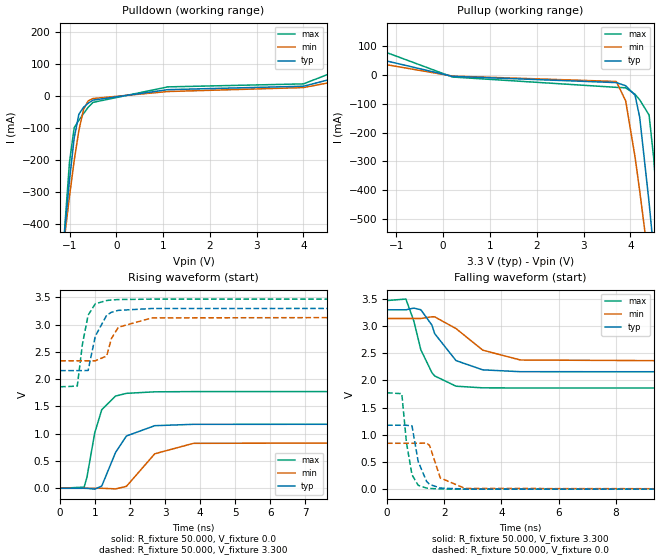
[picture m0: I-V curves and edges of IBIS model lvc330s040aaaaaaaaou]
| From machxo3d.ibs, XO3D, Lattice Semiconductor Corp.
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|   Model lvc330s040aaaaaaaaou
[Model] lvc330s040aaaaaaaaou
Model_type Output
Polarity   Non-Inverting
Enable   Active-High
Vmeas =  1.650V
Cref =  0.0F
Rref =  1.000M
Vref =  0.0V
C_comp   4.200pF   3.800pF   7.500pF
[Temperature Range]   25.000   0.105k   -40.000
[Voltage Range]   3.300V   3.140V   3.470V
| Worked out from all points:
|   slope of the pulldown table from 0 to 0.495 V, typ, clamps not added: 48.6 ohm
|   slope of the pullup table from 0 to 0.495 V, typ, clamps not added: 53.4 ohm
|   rising waveform, R_fixture 50.000, V_fixture 0.0: 20-80 % time 531ps typ, 717ps min, 364ps max; typ from 0 V to 1.18 V
|   rising waveform, R_fixture 50.000, V_fixture 3.300: 20-80 % time 315ps typ, 358ps min, 237ps max; typ from 2.16 V to 3.3 V
|   falling waveform, R_fixture 50.000, V_fixture 3.300: 20-80 % time 894ps typ, 1.23ns min, 631ps max; typ from 3.3 V to 2.16 V
|   falling waveform, R_fixture 50.000, V_fixture 0.0: 20-80 % time 321ps typ, 376ps min, 256ps max; typ from 1.18 V to 0 V
[Pulldown]
|Voltage   I(typ)   I(min)   I(max)
-3.3V     -4.507A    -3.482A    -6.263A
-1.1V     -420mA     -435.9mA   -408.3mA
-1V       -263.3mA   -314.6mA   -207mA
-900mV    -132.6mA   -203.2mA   -100.5mA
-800mV    -58.22mA   -109.1mA   -77.24mA
-700mV    -36.75mA   -43.32mA   -56.27mA
-600mV    -23.7mA    -16.39mA   -36.49mA
-500mV    -14.27mA   -9.199mA   -21.38mA
1.1V      18.49mA    12.63mA    27.15mA
4V        29.22mA    25mA       36.5mA
5.3V      77.78mA    61.08mA    110.5mA
6.6V      140.9mA    104mA      211.7mA
[Pullup]
|Voltage   I(typ)   I(min)   I(max)
-3.3V     100.8mA    70.89mA    162.3mA
-2.4V     95.01mA    70.07mA    150.9mA
200mV     -4.043mA   -3.026mA   -6.273mA
3.7V      -25.75mA   -21.88mA   -42.22mA
3.9V      -36.65mA   -89.28mA   -43.81mA
4.1V      -69.34mA   -284.1mA   -66.52mA
4.2V      -146.7mA   -403mA     -85.68mA
4.4V      -442.7mA   -658.2mA   -138.5mA
4.5V      -613.1mA   -790.6mA   -290.1mA
4.6V      -789.1mA   -924.9mA   -514mA
4.7V      -968.5mA   -1.061A    -759.1mA
6.6V      -4.534A    -3.729A    -5.846A
[Ramp]
| variable   typ   min   max
dV/dt_r   0.705/0.532n   0.507/0.718n   1.064/0.364n
dV/dt_f   0.685/0.893n   0.481/1.230n   0.965/0.635n
R_load = 50.000
[Rising Waveform]
R_fixture= 50.000
V_fixture= 0.0
V_fixture_min= 0.0
V_fixture_max= 0.0
|time   V(typ)   V(min)   V(max)
0s        27.69nV    65.53nV    348nV
686ps     548.6uV    -4.481uV   21.31mV
767ps     -959.7uV   -4.481uV   207.2mV
988ps     -16.21mV   99.54uV    1.018V
1.189ns   42.59mV    28.29uV    1.442V
1.584ns   659mV      -10.97mV   1.692V
1.893ns   959mV      35.75mV    1.741V
2.702ns   1.148V     632.6mV    1.769V
3.809ns   1.173V     824.5mV    1.773V
20ns      1.176V     844.4mV    1.773V
[Rising Waveform]
R_fixture= 50.000
V_fixture= 3.300
V_fixture_min= 3.140
V_fixture_max= 3.470
|time   V(typ)   V(min)   V(max)
0s        2.158V     2.338V     1.861V
489ps     2.158V     2.338V     1.874V
636ps     2.158V     2.338V     2.642V
799ps     2.161V     2.338V     3.175V
1.004ns   2.79V      2.338V     3.384V
1.33ns    3.175V     2.426V     3.444V
1.462ns   3.227V     2.743V     3.453V
1.663ns   3.263V     2.954V     3.461V
2.627ns   3.297V     3.125V     3.469V
20ns      3.3V       3.14V      3.47V
[Falling Waveform]
R_fixture= 50.000
V_fixture= 3.300
V_fixture_min= 3.140
V_fixture_max= 3.470
|time   V(typ)   V(min)   V(max)
0s        3.3V       3.14V      3.47V
659ps     3.299V     3.14V      3.497V
936ps     3.331V     3.14V      3.096V
1.181ns   3.301V     3.139V     2.566V
1.571ns   3.017V     3.171V     2.142V
1.666ns   2.861V     3.17V      2.083V
2.413ns   2.365V     2.954V     1.894V
3.348ns   2.195V     2.557V     1.864V
4.664ns   2.161V     2.376V     1.861V
20ns      2.158V     2.338V     1.861V
[Falling Waveform]
R_fixture= 50.000
V_fixture= 0.0
V_fixture_min= 0.0
V_fixture_max= 0.0
|time   V(typ)   V(min)   V(max)
0s        1.176V     844.4mV    1.773V
516ps     1.176V     844.4mV    1.757V
680ps     1.175V     844.5mV    853.9mV
873ps     1.165V     844.5mV    264.7mV
1.09ns    508.3mV    844.3mV    70.45mV
1.384ns   142.2mV    848mV      19.79mV
1.491ns   87.66mV    802.1mV    13.71mV
1.862ns   20.44mV    205.8mV    3.453mV
2.73ns    1.92mV     13.57mV    255.9uV
20ns      39.7nV     133.1nV    372nV
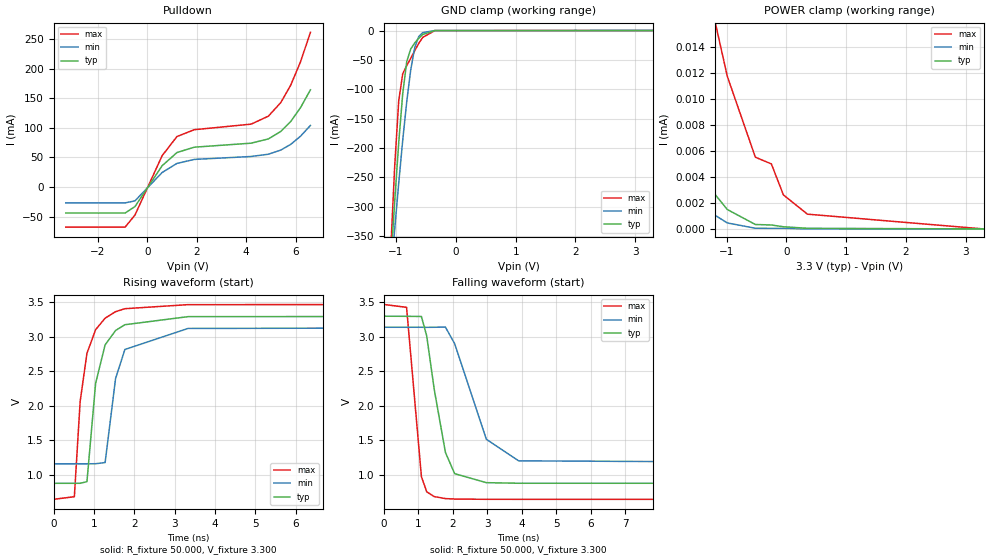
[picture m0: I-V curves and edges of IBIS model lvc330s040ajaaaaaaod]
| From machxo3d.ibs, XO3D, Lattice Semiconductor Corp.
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|   Model lvc330s040ajaaaaaaod
[Model] lvc330s040ajaaaaaaod
Model_type I/O_open_drain
Polarity   Non-Inverting
Enable   Active-Low
Vinl =  0.800V
Vinh =  2.000V
Vmeas =  1.650V
Cref =  0.0F
Rref = 10.00k
Vref = 3.30V
C_comp   4.200pF   3.800pF   7.500pF
[Temperature Range]   25.000   0.105k   -40.000
[Voltage Range]   3.300V   3.140V   3.470V
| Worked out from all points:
|   slope of the pulldown table from 0 to 0.495 V, typ, clamps not added: 16.2 ohm
|   GND clamp passes 1 mA (typ) near -0.43 V on its own axis
|   rising waveform, R_fixture 50.000, V_fixture 3.300: 20-80 % time 324ps typ, 328ps min, 327ps max; typ from 0.878 V to 3.3 V
|   falling waveform, R_fixture 50.000, V_fixture 3.300: 20-80 % time 465ps typ, 783ps min, 263ps max; typ from 3.3 V to 0.878 V
[Pulldown]
|Voltage   I(typ)   I(min)   I(max)
-3.3V     -43.98mA   -26.85mA   -67.81mA
-900mV    -43.98mA   -26.85mA   -67.81mA
-500mV    -33.06mA   -23.42mA   -47.39mA
600mV     35.86mA    24.47mA    52.84mA
1.2V      58.2mA     39.81mA    85.22mA
1.9V      67.18mA    46.53mA    96.69mA
4.2V      73.98mA    51.49mA    106.1mA
4.9V      81.14mA    55.32mA    119.6mA
5.4V      93.79mA    62.3mA     142.5mA
5.8V      110.5mA    71.89mA    171.7mA
6.2V      134mA      85.76mA    211.4mA
6.6V      164mA      103.9mA    261.1mA
[GND_clamp]
|Voltage   I(typ)   I(min)   I(max)
-3.3V     -4.507A    -3.482A    -6.263A
-1.089V   -398.4mA   -420.6mA   -374.7mA
-1.022V   -290.7mA   -338.6mA   -230.6mA
-955mV    -191.3mA   -260.2mA   -120mA
-888mV    -107.5mA   -187mA     -73.64mA
-821mV    -52.96mA   -121.4mA   -59.79mA
-754mV    -31.36mA   -66.92mA   -47.4mA
-687mV    -21.12mA   -28.79mA   -34.18mA
-620mV    -13.16mA   -10.19mA   -21.93mA
-553mV    -6.814mA   -3.53mA    -11.64mA
-352mV    -96.36uA   -46.21uA   -149.8uA
3.3V      0A         0A         0A
[POWER_clamp]
|Voltage   I(typ)   I(min)   I(max)
-3.3V     732.2uA    455.9uA    1.265mA
-2.663V   69.44uA    15.46uA    306.8uA
-2.529V   27.69uA    10.95uA    164.1uA
-2.328V   15.69uA    8.498uA    64.68uA
-1.725V   7.348uA    3.693uA    30.69uA
-1.189V   2.632uA    1.04uA     15.85uA
-988mV    1.494uA    463.1nA    11.72uA
-519mV    342.8nA    54.77nA    5.51uA
-251mV    305.1nA    47.64nA    4.994uA
-50mV     169nA      47.64nA    2.616uA
352mV     50.67nA    4.149nA    1.135uA
3.3V      0A         0A         0A
[Ramp]
| variable   typ   min   max
dV/dt_r   1.453/0.323n   1.187/0.327n   1.694/0.328n
dV/dt_f   1.453/0.465n   1.187/0.783n   1.694/0.262n
R_load = 50.000
[Rising Waveform]
R_fixture= 50.000
V_fixture= 3.300
V_fixture_min= 3.140
V_fixture_max= 3.470
|time   V(typ)   V(min)   V(max)
0s        878.1mV    1.161V     645.8mV
516ps     878.1mV    1.161V     683.7mV
660ps     878.6mV    1.161V     2.067V
828ps     901.9mV    1.161V     2.762V
1.043ns   2.328V     1.162V     3.105V
1.278ns   2.885V     1.179V     3.272V
1.537ns   3.093V     2.397V     3.366V
1.768ns   3.177V     2.818V     3.409V
3.334ns   3.294V     3.123V     3.468V
20ns      3.3V       3.14V      3.47V
[Falling Waveform]
R_fixture= 50.000
V_fixture= 3.300
V_fixture_min= 3.140
V_fixture_max= 3.470
|time   V(typ)   V(min)   V(max)
0s        3.3V       3.14V      3.47V
654ps     3.299V     3.14V      3.429V
1.085ns   3.296V     3.14V      975.6mV
1.239ns   3.014V     3.139V     754.8mV
1.459ns   2.235V     3.14V      685.2mV
1.783ns   1.325V     3.142V     656.6mV
2.051ns   1.018V     2.902V     649.9mV
2.972ns   887.4mV    1.516V     646.1mV
3.91ns    878.9mV    1.204V     645.8mV
20ns      878mV      1.161V     645.8mV
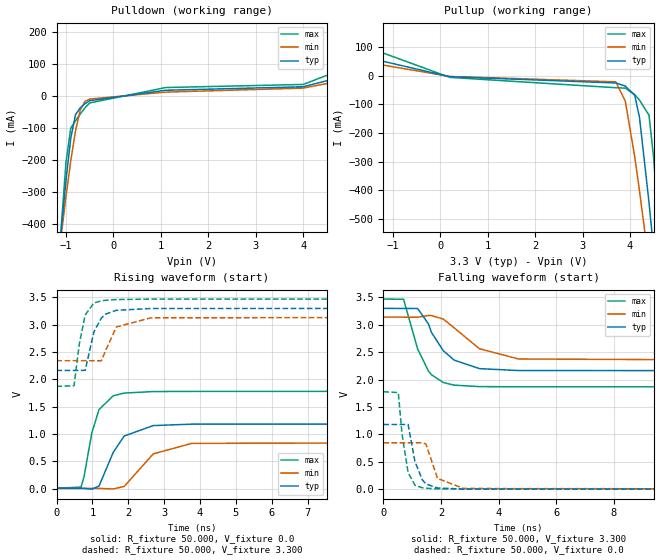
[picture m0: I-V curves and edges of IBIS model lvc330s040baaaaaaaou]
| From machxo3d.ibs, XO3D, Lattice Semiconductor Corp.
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|   Model lvc330s040baaaaaaaou
[Model] lvc330s040baaaaaaaou
Model_type Output
Polarity   Non-Inverting
Enable   Active-High
Vmeas =  1.650V
Cref =  0.0F
Rref =  1.000M
Vref =  0.0V
C_comp   4.200pF   3.800pF   7.500pF
[Temperature Range]   25.000   0.105k   -40.000
[Voltage Range]   3.300V   3.140V   3.470V
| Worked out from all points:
|   slope of the pulldown table from 0 to 0.495 V, typ, clamps not added: 48.6 ohm
|   slope of the pullup table from 0 to 0.495 V, typ, clamps not added: 53.2 ohm
|   rising waveform, R_fixture 50.000, V_fixture 0.0: 20-80 % time 531ps typ, 717ps min, 362ps max; typ from 0.003 V to 1.18 V
|   rising waveform, R_fixture 50.000, V_fixture 3.300: 20-80 % time 313ps typ, 356ps min, 236ps max; typ from 2.16 V to 3.3 V
|   falling waveform, R_fixture 50.000, V_fixture 3.300: 20-80 % time 887ps typ, 1.24ns min, 634ps max; typ from 3.3 V to 2.16 V
|   falling waveform, R_fixture 50.000, V_fixture 0.0: 20-80 % time 324ps typ, 377ps min, 258ps max; typ from 1.18 V to 0.003 V
[Pulldown]
|Voltage   I(typ)   I(min)   I(max)
-3.3V     -4.507A    -3.482A    -6.263A
-1.1V     -420mA     -435.9mA   -408.3mA
-1V       -263.3mA   -314.6mA   -207.1mA
-900mV    -132.7mA   -203.2mA   -100.5mA
-800mV    -58.28mA   -109.1mA   -77.32mA
-700mV    -36.82mA   -43.36mA   -56.37mA
-600mV    -23.77mA   -16.45mA   -36.61mA
-500mV    -14.37mA   -9.275mA   -21.53mA
1.1V      18.35mA    12.55mA    26.91mA
4V        29.28mA    25.1mA     36.55mA
5.3V      78.49mA    62.34mA    110.9mA
6.6V      143.9mA    108.8mA    214.3mA
[Pullup]
|Voltage   I(typ)   I(min)   I(max)
-3.3V     102.5mA    72.81mA    163.9mA
-2.5V     99.18mA    72.81mA    156.9mA
200mV     -4.064mA   -3.041mA   -6.306mA
3.7V      -25.88mA   -21.94mA   -42.46mA
3.9V      -36.73mA   -89.31mA   -43.99mA
4.1V      -69.39mA   -284.1mA   -66.62mA
4.2V      -146.7mA   -403mA     -85.76mA
4.4V      -442.8mA   -658.2mA   -138.5mA
4.5V      -613.1mA   -790.6mA   -290.2mA
4.6V      -789.1mA   -924.9mA   -514mA
4.7V      -968.6mA   -1.061A    -759.2mA
6.6V      -4.534A    -3.729A    -5.846A
[Ramp]
| variable   typ   min   max
dV/dt_r   0.707/0.532n   0.508/0.720n   1.065/0.363n
dV/dt_f   0.682/0.894n   0.480/1.224n   0.960/0.631n
R_load = 50.000
[Rising Waveform]
R_fixture= 50.000
V_fixture= 0.0
V_fixture_min= 0.0
V_fixture_max= 0.0
|time   V(typ)   V(min)   V(max)
0s        3.283mV    2.496mV    4.478mV
684ps     3.816mV    2.49mV     27.03mV
767ps     2.234mV    2.49mV     216.7mV
984ps     -11.68mV   2.56mV     1.017V
1.185ns   44.37mV    2.512mV    1.446V
1.582ns   662.8mV    -7.097mV   1.699V
1.887ns   961.9mV    38.18mV    1.748V
2.696ns   1.153V     634.1mV    1.776V
3.77ns    1.179V     827.2mV    1.779V
20ns      1.182V     848.7mV    1.78V
[Rising Waveform]
R_fixture= 50.000
V_fixture= 3.300
V_fixture_min= 3.140
V_fixture_max= 3.470
|time   V(typ)   V(min)   V(max)
0s        2.163V     2.341V     1.87V
489ps     2.163V     2.341V     1.883V
636ps     2.163V     2.341V     2.65V
799ps     2.165V     2.341V     3.179V
1.044ns   2.871V     2.341V     3.399V
1.251ns   3.122V     2.34V      3.437V
1.373ns   3.196V     2.534V     3.448V
1.67ns    3.264V     2.959V     3.461V
2.627ns   3.297V     3.126V     3.469V
20ns      3.3V       3.14V      3.47V
[Falling Waveform]
R_fixture= 50.000
V_fixture= 3.300
V_fixture_min= 3.140
V_fixture_max= 3.470
|time   V(typ)   V(min)   V(max)
0s        3.3V       3.14V      3.47V
700ps     3.299V     3.14V      3.466V
1.186ns   3.298V     3.139V     2.562V
1.564ns   3.017V     3.17V      2.156V
1.663ns   2.865V     3.17V      2.092V
2.078ns   2.528V     3.105V     1.948V
2.452ns   2.357V     2.946V     1.9V
3.331ns   2.201V     2.564V     1.873V
4.69ns    2.166V     2.377V     1.87V
20ns      2.163V     2.341V     1.87V
[Falling Waveform]
R_fixture= 50.000
V_fixture= 0.0
V_fixture_min= 0.0
V_fixture_max= 0.0
|time   V(typ)   V(min)   V(max)
0s        1.182V     848.7mV    1.78V
516ps     1.182V     848.6mV    1.764V
648ps     1.182V     848.6mV    999.6mV
857ps     1.182V     848.8mV    305.6mV
1.094ns   507.1mV    848.6mV    74.66mV
1.348ns   175mV      850.1mV    27.81mV
1.471ns   99.51mV    829.5mV    19.55mV
1.881ns   23.1mV     197.7mV    7.787mV
2.786ns   4.98mV     14.73mV    4.704mV
20ns      3.283mV    2.496mV    4.478mV
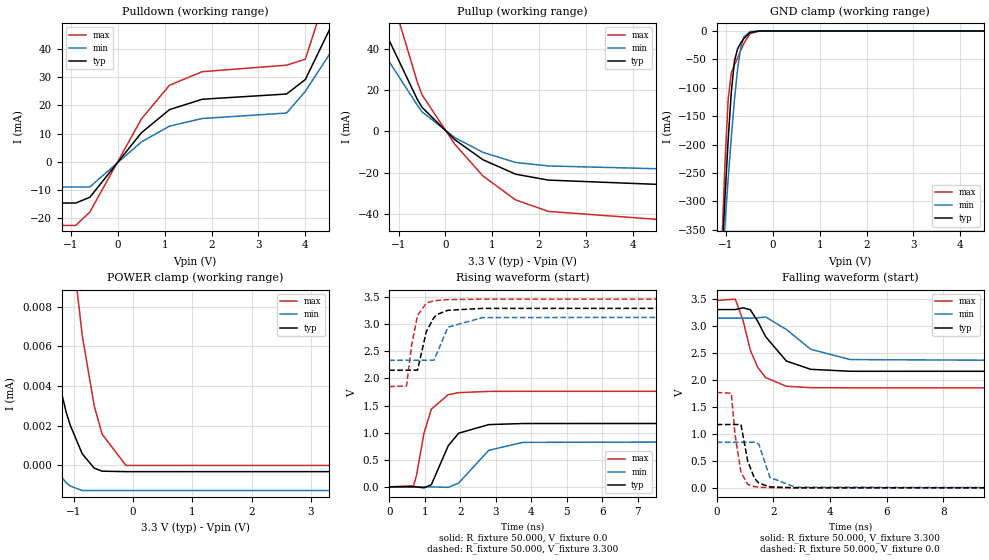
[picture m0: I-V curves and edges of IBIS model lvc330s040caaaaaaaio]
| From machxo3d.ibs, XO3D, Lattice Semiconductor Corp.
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|   Model lvc330s040caaaaaaaio
[Model] lvc330s040caaaaaaaio
Model_type I/O
Polarity   Non-Inverting
Enable   Active-Low
Vinl =  0.800V
Vinh =  2.000V
Vmeas =  1.650V
Cref =  0.0F
Rref =  1.000M
Vref =  0.0V
C_comp   4.200pF   3.800pF   7.500pF
[Temperature Range]   25.000   0.105k   -40.000
[Voltage Range]   3.300V   3.140V   3.470V
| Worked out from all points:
|   slope of the pulldown table from 0 to 0.495 V, typ, clamps not added: 48.6 ohm
|   slope of the pullup table from 0 to 0.495 V, typ, clamps not added: 53.4 ohm
|   GND clamp passes 1 mA (typ) near -0.43 V on its own axis
|   rising waveform, R_fixture 50.000, V_fixture 0.0: 20-80 % time 531ps typ, 712ps min, 364ps max; typ from 0 V to 1.17 V
|   rising waveform, R_fixture 50.000, V_fixture 3.300: 20-80 % time 316ps typ, 360ps min, 238ps max; typ from 2.15 V to 3.3 V
|   falling waveform, R_fixture 50.000, V_fixture 3.300: 20-80 % time 888ps typ, 1.23ns min, 636ps max; typ from 3.3 V to 2.15 V
|   falling waveform, R_fixture 50.000, V_fixture 0.0: 20-80 % time 319ps typ, 373ps min, 254ps max; typ from 1.17 V to 0 V
[Pulldown]
|Voltage   I(typ)   I(min)   I(max)
-3.3V     -14.66mA   -8.951mA   -22.6mA
-900mV    -14.66mA   -8.951mA   -22.6mA
-600mV    -12.62mA   -8.951mA   -17.88mA
500mV     10.27mA    7.01mA     15.14mA
1.1V      18.49mA    12.63mA    27.15mA
1.8V      22.18mA    15.35mA    31.97mA
3.6V      24.04mA    17.29mA    34.28mA
4V        29.18mA    25mA       36.39mA
4.6V      49.76mA    40.29mA    67.32mA
5V        65.2mA     51.84mA    90.92mA
5.5V      86.62mA    67.51mA    124.3mA
6.6V      140.3mA    103.4mA    211mA
[Pullup]
|Voltage   I(typ)   I(min)   I(max)
-3.3V     100.8mA    70.91mA    162mA
-2.7V     100.8mA    70.91mA    162mA
-2.5V     97.81mA    70.91mA    155.6mA
-2.2V     88.28mA    66.04mA    139.8mA
-1.7V     67.91mA    51.33mA    107.4mA
-600mV    15.51mA    12.76mA    23.9mA
-500mV    11.68mA    9.5mA      17.79mA
200mV     -4.043mA   -3.026mA   -6.275mA
800mV     -13.76mA   -10.18mA   -21.62mA
1.5V      -20.8mA    -15.09mA   -33.3mA
2.2V      -23.66mA   -16.79mA   -38.85mA
6.6V      -27.59mA   -19.35mA   -46.21mA
[GND_clamp]
|Voltage   I(typ)   I(min)   I(max)
-3.3V     -4.507A    -3.482A    -6.263A
-1.089V   -398.4mA   -420.6mA   -374.7mA
-1.022V   -290.7mA   -338.6mA   -230.6mA
-955mV    -191.4mA   -260.2mA   -120.1mA
-888mV    -107.5mA   -187mA     -73.7mA
-821mV    -53mA      -121.4mA   -59.85mA
-754mV    -31.41mA   -66.94mA   -47.47mA
-687mV    -21.17mA   -28.82mA   -34.25mA
-620mV    -13.21mA   -10.23mA   -22mA
-486mV    -2.63mA    -1.112mA   -4.479mA
-285mV    -80.91uA   -42.41uA   -152.3uA
6.6V      121.2uA    55.82uA    291.2uA
[POWER_clamp]
|Voltage   I(typ)   I(min)   I(max)
-3.3V     704.7uA    440.9uA    1.167mA
-2.596V   46.79uA    12.42uA    184.2uA
-2.328V   25.67uA    8.107uA    76.87uA
-1.792V   13.09uA    2.762uA    43.68uA
-1.39V    5.98uA     124.1nA    24.26uA
-1.122V   2.656uA    -886.1nA   13.98uA
-1.055V   2.02uA     -1.042uA   11.85uA
-854mV    585.6nA    -1.267uA   6.557uA
-653mV    -133.8nA   -1.267uA   3.017uA
-519mV    -290.6nA   -1.267uA   1.58uA
-117mV    -313.6nA   -1.267uA   0A
3.3V      -313.6nA   -1.267uA   0A
[Ramp]
| variable   typ   min   max
dV/dt_r   0.703/0.532n   0.506/0.719n   1.059/0.365n
dV/dt_f   0.687/0.894n   0.481/1.230n   0.969/0.630n
R_load = 50.000
[Rising Waveform]
R_fixture= 50.000
V_fixture= 0.0
V_fixture_min= 0.0
V_fixture_max= 0.0
|time   V(typ)   V(min)   V(max)
0s        27.06nV    64.78nV    334.4nV
686ps     555uV      -1.878uV   21.47mV
767ps     -1.047mV   -1.878uV   207.2mV
983ps     -18.56mV   119.4uV    998.7mV
1.189ns   41.81mV    41.05uV    1.435V
1.663ns   758.2mV    -9.15mV    1.702V
1.956ns   990mV      68.94mV    1.739V
2.805ns   1.149V     674.3mV    1.762V
3.762ns   1.169V     820.9mV    1.764V
20ns      1.171V     842.7mV    1.765V
[Rising Waveform]
R_fixture= 50.000
V_fixture= 3.300
V_fixture_min= 3.140
V_fixture_max= 3.470
|time   V(typ)   V(min)   V(max)
0s        2.153V     2.336V     1.85V
489ps     2.153V     2.336V     1.864V
634ps     2.153V     2.336V     2.623V
799ps     2.156V     2.336V     3.166V
1.048ns   2.869V     2.337V     3.394V
1.258ns   3.122V     2.338V     3.432V
1.354ns   3.183V     2.478V     3.441V
1.655ns   3.259V     2.948V     3.456V
2.629ns   3.294V     3.124V     3.465V
20ns      3.297V     3.139V     3.465V
[Falling Waveform]
R_fixture= 50.000
V_fixture= 3.300
V_fixture_min= 3.140
V_fixture_max= 3.470
|time   V(typ)   V(min)   V(max)
0s        3.297V     3.139V     3.465V
657ps     3.297V     3.139V     3.49V
935ps     3.329V     3.139V     3.087V
1.186ns   3.294V     3.138V     2.547V
1.45ns    3.079V     3.144V     2.226V
1.726ns   2.797V     3.161V     2.04V
2.459ns   2.345V     2.929V     1.879V
3.32ns    2.192V     2.563V     1.853V
4.714ns   2.156V     2.372V     1.85V
20ns      2.153V     2.336V     1.85V
[Falling Waveform]
R_fixture= 50.000
V_fixture= 0.0
V_fixture_min= 0.0
V_fixture_max= 0.0
|time   V(typ)   V(min)   V(max)
0s        1.171V     842.7mV    1.765V
516ps     1.171V     842.6mV    1.749V
647ps     1.171V     842.7mV    985.1mV
857ps     1.171V     842.7mV    288.2mV
1.094ns   495.7mV    842.5mV    65.29mV
1.336ns   175.4mV    843.5mV    22.81mV
1.485ns   87.81mV    808.3mV    12.9mV
1.881ns   18.74mV    191.9mV    3.431mV
2.782ns   1.671mV    11.75mV    256.6uV
20ns      32.05nV    128nV      313.9nV
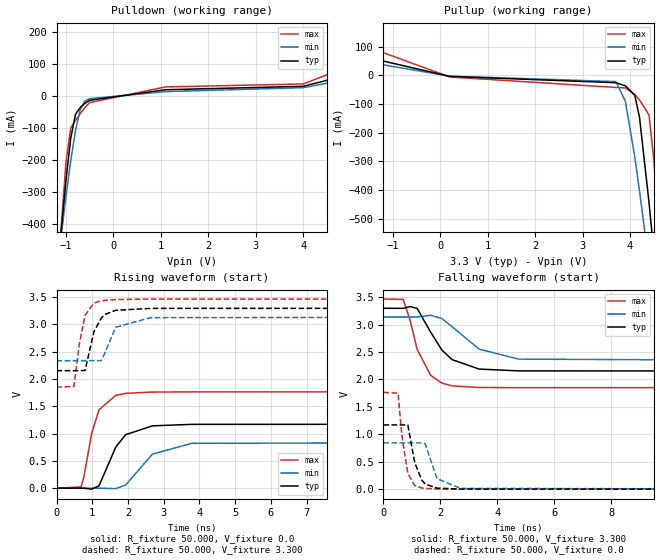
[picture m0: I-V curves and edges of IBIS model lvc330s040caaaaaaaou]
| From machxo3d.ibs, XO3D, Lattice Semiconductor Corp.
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|   Model lvc330s040caaaaaaaou
[Model] lvc330s040caaaaaaaou
Model_type Output
Polarity   Non-Inverting
Enable   Active-High
Vmeas =  1.650V
Cref =  0.0F
Rref =  1.000M
Vref =  0.0V
C_comp   4.200pF   3.800pF   7.500pF
[Temperature Range]   25.000   0.105k   -40.000
[Voltage Range]   3.300V   3.140V   3.470V
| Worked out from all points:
|   slope of the pulldown table from 0 to 0.495 V, typ, clamps not added: 48.2 ohm
|   slope of the pullup table from 0 to 0.495 V, typ, clamps not added: 53.4 ohm
|   rising waveform, R_fixture 50.000, V_fixture 0.0: 20-80 % time 529ps typ, 717ps min, 365ps max; typ from 0 V to 1.17 V
|   rising waveform, R_fixture 50.000, V_fixture 3.300: 20-80 % time 316ps typ, 360ps min, 238ps max; typ from 2.15 V to 3.3 V
|   falling waveform, R_fixture 50.000, V_fixture 3.300: 20-80 % time 890ps typ, 1.22ns min, 635ps max; typ from 3.3 V to 2.15 V
|   falling waveform, R_fixture 50.000, V_fixture 0.0: 20-80 % time 318ps typ, 372ps min, 254ps max; typ from 1.17 V to 0 V
[Pulldown]
|Voltage   I(typ)   I(min)   I(max)
-3.3V     -4.507A    -3.482A    -6.263A
-1.1V     -420mA     -435.9mA   -408.3mA
-1V       -263.3mA   -314.6mA   -207.1mA
-900mV    -132.7mA   -203.2mA   -100.5mA
-800mV    -58.26mA   -109.1mA   -77.3mA
-700mV    -36.8mA    -43.35mA   -56.34mA
-600mV    -23.75mA   -16.43mA   -36.57mA
-500mV    -14.34mA   -9.251mA   -21.48mA
1.1V      18.59mA    12.67mA    27.38mA
4V        29.29mA    25.04mA    36.66mA
5.3V      77.91mA    61.15mA    110.8mA
6.6V      141.1mA    104.1mA    212.2mA
[Pullup]
|Voltage   I(typ)   I(min)   I(max)
-3.3V     101mA      70.97mA    162.6mA
-2.4V     95.16mA    70.15mA    151.2mA
200mV     -3.936mA   -2.986mA   -6.02mA
3.7V      -25.83mA   -21.92mA   -42.32mA
3.9V      -36.71mA   -89.3mA    -43.93mA
4.1V      -69.38mA   -284.1mA   -66.59mA
4.2V      -146.7mA   -403mA     -85.74mA
4.4V      -442.8mA   -658.2mA   -138.5mA
4.5V      -613.1mA   -790.6mA   -290.2mA
4.6V      -789.1mA   -924.9mA   -514mA
4.7V      -968.5mA   -1.061A    -759.2mA
6.6V      -4.534A    -3.729A    -5.846A
[Ramp]
| variable   typ   min   max
dV/dt_r   0.703/0.532n   0.506/0.719n   1.059/0.365n
dV/dt_f   0.687/0.894n   0.481/1.230n   0.969/0.630n
R_load = 50.000
[Rising Waveform]
R_fixture= 50.000
V_fixture= 0.0
V_fixture_min= 0.0
V_fixture_max= 0.0
|time   V(typ)   V(min)   V(max)
0s        27.06nV    64.78nV    334.4nV
686ps     546.1uV    -4.532uV   21.47mV
767ps     -965.5uV   -4.532uV   207.2mV
983ps     -18.56mV   99.47uV    998.8mV
1.189ns   41.81mV    25.16uV    1.435V
1.659ns   753.6mV    -9.15mV    1.7V
1.935ns   979.2mV    57.37mV    1.737V
2.685ns   1.142V     623.3mV    1.761V
3.785ns   1.169V     821.9mV    1.764V
20ns      1.171V     842.7mV    1.765V
[Rising Waveform]
R_fixture= 50.000
V_fixture= 3.300
V_fixture_min= 3.140
V_fixture_max= 3.470
|time   V(typ)   V(min)   V(max)
0s        2.153V     2.336V     1.85V
489ps     2.153V     2.336V     1.864V
634ps     2.153V     2.336V     2.623V
799ps     2.156V     2.336V     3.166V
1.048ns   2.869V     2.337V     3.394V
1.258ns   3.122V     2.338V     3.432V
1.354ns   3.183V     2.478V     3.441V
1.655ns   3.259V     2.948V     3.456V
2.629ns   3.294V     3.124V     3.465V
20ns      3.297V     3.139V     3.465V
[Falling Waveform]
R_fixture= 50.000
V_fixture= 3.300
V_fixture_min= 3.140
V_fixture_max= 3.470
|time   V(typ)   V(min)   V(max)
0s        3.297V     3.139V     3.465V
698ps     3.296V     3.139V     3.459V
935ps     3.328V     3.139V     3.085V
1.186ns   3.294V     3.138V     2.547V
1.659ns   2.863V     3.169V     2.076V
2.053ns   2.536V     3.111V     1.933V
2.413ns   2.361V     2.961V     1.883V
3.361ns   2.189V     2.552V     1.853V
4.748ns   2.156V     2.37V      1.85V
20ns      2.153V     2.336V     1.85V
[Falling Waveform]
R_fixture= 50.000
V_fixture= 0.0
V_fixture_min= 0.0
V_fixture_max= 0.0
|time   V(typ)   V(min)   V(max)
0s        1.171V     842.7mV    1.765V
516ps     1.171V     842.7mV    1.749V
647ps     1.171V     842.7mV    985.1mV
857ps     1.171V     842.8mV    288.3mV
1.1ns     484mV      842.6mV    64.24mV
1.348ns   165.7mV    843.9mV    21.87mV
1.467ns   94.32mV    827mV      14.53mV
1.885ns   18.62mV    189.4mV    3.104mV
2.716ns   1.908mV    13.87mV    271.9uV
20ns      31.7nV     125.9nV    353nV
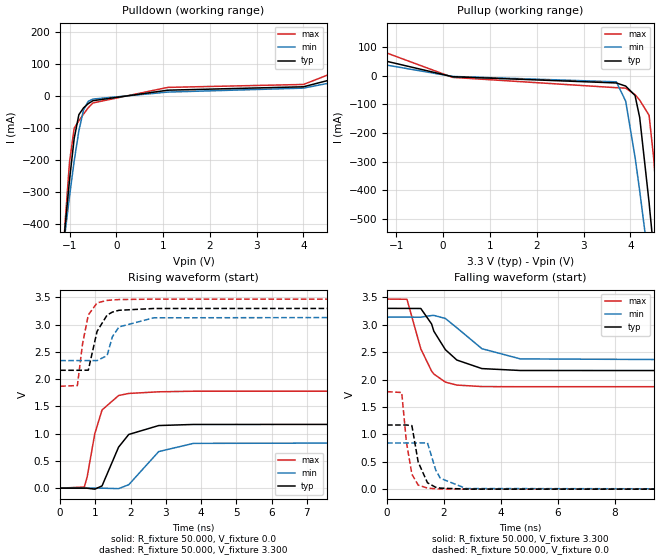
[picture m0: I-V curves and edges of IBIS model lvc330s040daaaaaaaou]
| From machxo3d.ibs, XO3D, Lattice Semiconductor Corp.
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|   Model lvc330s040daaaaaaaou
[Model] lvc330s040daaaaaaaou
Model_type Output
Polarity   Non-Inverting
Enable   Active-High
Vmeas =  1.650V
Cref =  0.0F
Rref =  1.000M
Vref =  0.0V
C_comp   4.200pF   3.800pF   7.500pF
[Temperature Range]   25.000   0.105k   -40.000
[Voltage Range]   3.300V   3.140V   3.470V
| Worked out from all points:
|   slope of the pulldown table from 0 to 0.495 V, typ, clamps not added: 48.2 ohm
|   slope of the pullup table from 0 to 0.495 V, typ, clamps not added: 53.2 ohm
|   rising waveform, R_fixture 50.000, V_fixture 0.0: 20-80 % time 532ps typ, 714ps min, 372ps max; typ from 0 V to 1.17 V
|   rising waveform, R_fixture 50.000, V_fixture 3.300: 20-80 % time 314ps typ, 357ps min, 236ps max; typ from 2.16 V to 3.3 V
|   falling waveform, R_fixture 50.000, V_fixture 3.300: 20-80 % time 890ps typ, 1.22ns min, 634ps max; typ from 3.3 V to 2.16 V
|   falling waveform, R_fixture 50.000, V_fixture 0.0: 20-80 % time 319ps typ, 374ps min, 260ps max; typ from 1.17 V to 0 V
[Pulldown]
|Voltage   I(typ)   I(min)   I(max)
-3.3V     -4.507A    -3.482A    -6.263A
-1.1V     -420mA     -435.9mA   -408.3mA
-1V       -263.3mA   -314.6mA   -207.1mA
-900mV    -132.7mA   -203.2mA   -100.5mA
-800mV    -58.26mA   -109.1mA   -77.3mA
-700mV    -36.8mA    -43.35mA   -56.34mA
-600mV    -23.75mA   -16.43mA   -36.57mA
-500mV    -14.34mA   -9.251mA   -21.48mA
1.1V      18.59mA    12.67mA    27.38mA
4V        29.28mA    25.1mA     36.55mA
5.3V      78.49mA    62.34mA    110.9mA
6.6V      143.9mA    108.8mA    214.3mA
[Pullup]
|Voltage   I(typ)   I(min)   I(max)
-3.3V     102.5mA    72.81mA    163.9mA
-2.5V     99.18mA    72.81mA    156.9mA
200mV     -4.064mA   -3.041mA   -6.306mA
3.7V      -25.83mA   -21.92mA   -42.32mA
3.9V      -36.71mA   -89.3mA    -43.93mA
4.1V      -69.38mA   -284.1mA   -66.59mA
4.2V      -146.7mA   -403mA     -85.74mA
4.4V      -442.8mA   -658.2mA   -138.5mA
4.5V      -613.1mA   -790.6mA   -290.2mA
4.6V      -789.1mA   -924.9mA   -514mA
4.7V      -968.5mA   -1.061A    -759.2mA
6.6V      -4.534A    -3.729A    -5.846A
[Ramp]
| variable   typ   min   max
dV/dt_r   0.703/0.532n   0.506/0.719n   1.068/0.373n
dV/dt_f   0.682/0.894n   0.480/1.224n   0.960/0.631n
R_load = 50.000
[Rising Waveform]
R_fixture= 50.000
V_fixture= 0.0
V_fixture_min= 0.0
V_fixture_max= 0.0
|time   V(typ)   V(min)   V(max)
0s        27.06nV    64.78nV    334.4nV
686ps     546.1uV    -4.466uV   21.47mV
767ps     -965.5uV   -4.466uV   207.2mV
983ps     -18.56mV   99.46uV    998.8mV
1.189ns   41.81mV    25.18uV    1.435V
1.659ns   753.6mV    -9.199mV   1.7V
1.947ns   985.4mV    63.62mV    1.738V
2.797ns   1.149V     671.3mV    1.768V
3.785ns   1.169V     821.9mV    1.779V
20ns      1.171V     842.7mV    1.78V
[Rising Waveform]
R_fixture= 50.000
V_fixture= 3.300
V_fixture_min= 3.140
V_fixture_max= 3.470
|time   V(typ)   V(min)   V(max)
0s        2.163V     2.341V     1.87V
489ps     2.163V     2.341V     1.883V
636ps     2.163V     2.341V     2.65V
799ps     2.165V     2.341V     3.179V
1.048ns   2.878V     2.341V     3.4V
1.332ns   3.176V     2.432V     3.445V
1.482ns   3.231V     2.779V     3.454V
1.67ns    3.264V     2.959V     3.461V
2.657ns   3.297V     3.126V     3.469V
20ns      3.3V       3.14V      3.47V
[Falling Waveform]
R_fixture= 50.000
V_fixture= 3.300
V_fixture_min= 3.140
V_fixture_max= 3.470
|time   V(typ)   V(min)   V(max)
0s        3.3V       3.14V      3.47V
700ps     3.299V     3.14V      3.466V
1.186ns   3.298V     3.139V     2.562V
1.564ns   3.017V     3.17V      2.156V
1.645ns   2.883V     3.172V     2.102V
2.048ns   2.547V     3.116V     1.954V
2.452ns   2.357V     2.946V     1.9V
3.331ns   2.201V     2.564V     1.873V
4.684ns   2.166V     2.378V     1.87V
20ns      2.163V     2.341V     1.87V
[Falling Waveform]
R_fixture= 50.000
V_fixture= 0.0
V_fixture_min= 0.0
V_fixture_max= 0.0
|time   V(typ)   V(min)   V(max)
0s        1.171V     842.7mV    1.78V
516ps     1.171V     842.7mV    1.764V
680ps     1.171V     842.8mV    863.7mV
873ps     1.16V      842.8mV    273.6mV
1.094ns   495.7mV    842.6mV    74.7mV
1.42ns    117.2mV    846.2mV    19.72mV
1.709ns   33.96mV    352.3mV    6.719mV
1.871ns   19.48mV    198.3mV    3.792mV
2.782ns   1.628mV    11.77mV    247uV
20ns      31.71nV    125.9nV    327.8nV
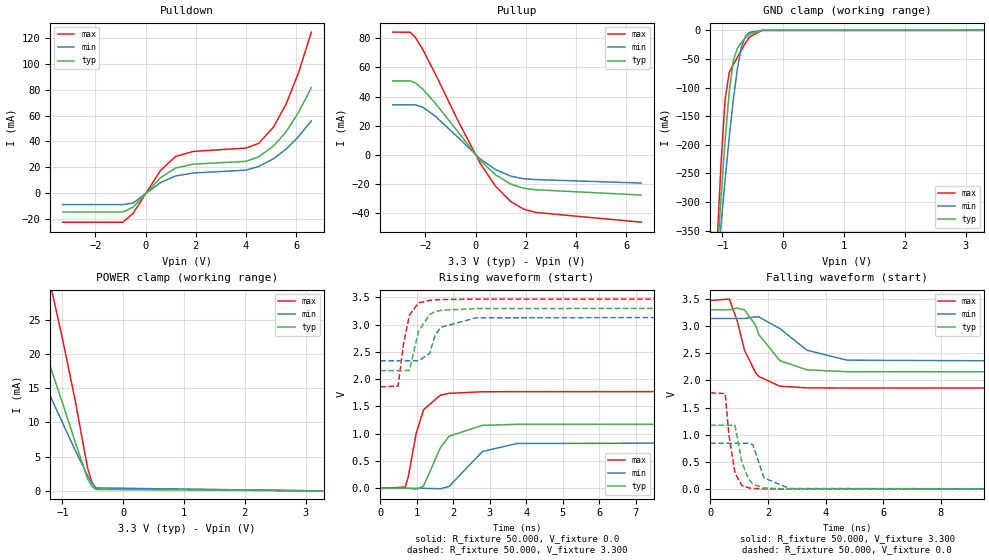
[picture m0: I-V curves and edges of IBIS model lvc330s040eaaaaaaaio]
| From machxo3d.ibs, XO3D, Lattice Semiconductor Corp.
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|   Model lvc330s040eaaaaaaaio
[Model] lvc330s040eaaaaaaaio
Model_type I/O
Polarity   Non-Inverting
Enable   Active-Low
Vinl =  0.800V
Vinh =  2.000V
Vmeas =  1.650V
Cref =  0.0F
Rref =  1.000M
Vref =  0.0V
C_comp   4.200pF   3.800pF   7.500pF
[Temperature Range]   25.000   0.105k   -40.000
[Voltage Range]   3.300V   3.140V   3.470V
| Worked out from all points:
|   slope of the pulldown table from 0 to 0.495 V, typ, clamps not added: 48.6 ohm
|   slope of the pullup table from 0 to 0.495 V, typ, clamps not added: 53.4 ohm
|   GND clamp passes 1 mA (typ) near -0.43 V on its own axis
|   POWER clamp passes 1 mA (typ) near -0.54 V on its own axis
|   rising waveform, R_fixture 50.000, V_fixture 0.0: 20-80 % time 531ps typ, 712ps min, 365ps max; typ from 0 V to 1.18 V
|   rising waveform, R_fixture 50.000, V_fixture 3.300: 20-80 % time 315ps typ, 358ps min, 237ps max; typ from 2.16 V to 3.3 V
|   falling waveform, R_fixture 50.000, V_fixture 3.300: 20-80 % time 894ps typ, 1.23ns min, 631ps max; typ from 3.3 V to 2.16 V
|   falling waveform, R_fixture 50.000, V_fixture 0.0: 20-80 % time 321ps typ, 376ps min, 257ps max; typ from 1.18 V to 0 V
[Pulldown]
|Voltage   I(typ)   I(min)   I(max)
-3.3V     -14.66mA   -8.951mA   -22.6mA
-900mV    -14.66mA   -8.951mA   -22.6mA
-500mV    -11.02mA   -7.807mA   -15.8mA
600mV     11.95mA    8.157mA    17.61mA
1.2V      19.4mA     13.27mA    28.41mA
1.9V      22.39mA    15.51mA    32.23mA
4V        24.55mA    17.73mA    34.86mA
4.5V      28.02mA    20.57mA    38.42mA
5.1V      36.45mA    26.6mA     51.27mA
5.6V      47.57mA    34.07mA    69.12mA
6.1V      62.73mA    43.93mA    93.72mA
6.6V      81.7mA     55.87mA    124.7mA
[Pullup]
|Voltage   I(typ)   I(min)   I(max)
-3.3V     50.71mA    34.32mA    84.22mA
-2.6V     50.71mA    34.32mA    84.08mA
-2.4V     49.45mA    34.32mA    80.61mA
-2.1V     45.03mA    32.7mA     72.26mA
-1.6V     35.33mA    26.42mA    55.44mA
-700mV    15.71mA    11.98mA    23.38mA
200mV     -4.043mA   -3.026mA   -6.275mA
800mV     -13.76mA   -10.18mA   -21.62mA
1.4V      -20.07mA   -14.6mA    -32.02mA
1.9V      -22.89mA   -16.38mA   -37.17mA
2.4V      -23.97mA   -16.98mA   -39.52mA
6.6V      -27.59mA   -19.35mA   -46.21mA
[GND_clamp]
|Voltage   I(typ)   I(min)   I(max)
-3.3V     -4.507A    -3.482A    -6.263A
-1.089V   -398.4mA   -420.6mA   -374.7mA
-1.022V   -290.7mA   -338.6mA   -230.6mA
-955mV    -191.3mA   -260.2mA   -120mA
-888mV    -107.5mA   -187mA     -73.64mA
-821mV    -52.96mA   -121.4mA   -59.79mA
-754mV    -31.36mA   -66.92mA   -47.4mA
-687mV    -21.12mA   -28.79mA   -34.18mA
-620mV    -13.16mA   -10.19mA   -21.93mA
-553mV    -6.814mA   -3.53mA    -11.64mA
-352mV    -96.36uA   -46.21uA   -149.8uA
3.3V      0A         0A         0A
[POWER_clamp]
|Voltage   I(typ)   I(min)   I(max)
-3.3V     59.07mA    46.89mA    89.53mA
-1.993V   37.2mA     28.86mA    58.21mA
-1.926V   35.72mA    27.66mA    56.06mA
-1.591V   27.93mA    21.43mA    44.68mA
-1.189V   17.86mA    13.66mA    29.77mA
-1.122V   16.11mA    12.35mA    27.14mA
-988mV    12.56mA    9.745mA    21.76mA
-787mV    7.078mA    5.887mA    13.07mA
-586mV    1.773mA    2.247mA    3.338mA
-519mV    707uA      1.205mA    1.383mA
-452mV    214.8uA    435.5uA    392.3uA
3.3V      0A         0A         0A
[Ramp]
| variable   typ   min   max
dV/dt_r   0.705/0.532n   0.507/0.718n   1.064/0.364n
dV/dt_f   0.685/0.893n   0.481/1.230n   0.965/0.635n
R_load = 50.000
[Rising Waveform]
R_fixture= 50.000
V_fixture= 0.0
V_fixture_min= 0.0
V_fixture_max= 0.0
|time   V(typ)   V(min)   V(max)
0s        27.69nV    65.53nV    348nV
686ps     557.4uV    -1.905uV   21.3mV
767ps     -962.8uV   -1.905uV   207.2mV
988ps     -16.16mV   119.5uV    1.018V
1.188ns   42.59mV    44.14uV    1.441V
1.648ns   742.9mV    -9.547mV   1.707V
1.884ns   953.5mV    31.8mV     1.741V
2.801ns   1.154V     674.2mV    1.77V
3.75ns    1.173V     822.1mV    1.772V
20ns      1.176V     844.4mV    1.773V
[Rising Waveform]
R_fixture= 50.000
V_fixture= 3.300
V_fixture_min= 3.140
V_fixture_max= 3.470
|time   V(typ)   V(min)   V(max)
0s        2.158V     2.338V     1.861V
489ps     2.158V     2.338V     1.874V
636ps     2.158V     2.338V     2.642V
799ps     2.161V     2.338V     3.175V
1.05ns    2.878V     2.339V     3.4V
1.35ns    3.184V     2.47V      3.446V
1.508ns   3.238V     2.815V     3.455V
1.663ns   3.263V     2.954V     3.461V
2.627ns   3.297V     3.126V     3.469V
20ns      3.3V       3.14V      3.47V
[Falling Waveform]
R_fixture= 50.000
V_fixture= 3.300
V_fixture_min= 3.140
V_fixture_max= 3.470
|time   V(typ)   V(min)   V(max)
0s        3.3V       3.14V      3.47V
659ps     3.299V     3.14V      3.497V
936ps     3.331V     3.14V      3.096V
1.189ns   3.297V     3.139V     2.553V
1.571ns   3.017V     3.171V     2.142V
1.684ns   2.843V     3.169V     2.073V
2.413ns   2.365V     2.954V     1.894V
3.348ns   2.195V     2.557V     1.864V
4.742ns   2.161V     2.373V     1.861V
20ns      2.158V     2.338V     1.861V
[Falling Waveform]
R_fixture= 50.000
V_fixture= 0.0
V_fixture_min= 0.0
V_fixture_max= 0.0
|time   V(typ)   V(min)   V(max)
0s        1.176V     844.4mV    1.773V
516ps     1.176V     844.3mV    1.757V
647ps     1.175V     844.5mV    994.9mV
857ps     1.175V     844.5mV    296.4mV
1.094ns   500.2mV    844.2mV    68.01mV
1.328ns   185.6mV    845mV      24.38mV
1.481ns   91.56mV    814.8mV    14.23mV
1.862ns   20.37mV    205.8mV    3.746mV
2.75ns    1.866mV    12.88mV    234.7uV
20ns      39.7nV     133.1nV    345.8nV
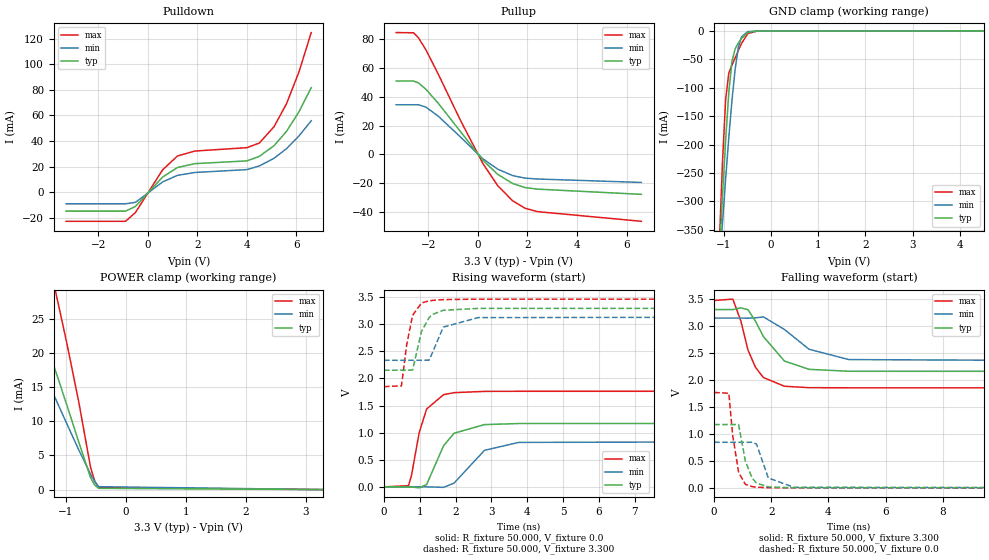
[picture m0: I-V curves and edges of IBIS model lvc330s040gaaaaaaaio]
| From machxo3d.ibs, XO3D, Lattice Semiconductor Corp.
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|   Model lvc330s040gaaaaaaaio
[Model] lvc330s040gaaaaaaaio
Model_type I/O
Polarity   Non-Inverting
Enable   Active-Low
Vinl =  0.800V
Vinh =  2.000V
Vmeas =  1.650V
Cref =  0.0F
Rref =  1.000M
Vref =  0.0V
C_comp   4.200pF   3.800pF   7.500pF
[Temperature Range]   25.000   0.105k   -40.000
[Voltage Range]   3.300V   3.140V   3.470V
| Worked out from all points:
|   slope of the pulldown table from 0 to 0.495 V, typ, clamps not added: 48.6 ohm
|   slope of the pullup table from 0 to 0.495 V, typ, clamps not added: 53.4 ohm
|   GND clamp passes 1 mA (typ) near -0.43 V on its own axis
|   POWER clamp passes 1 mA (typ) near -0.54 V on its own axis
|   rising waveform, R_fixture 50.000, V_fixture 0.0: 20-80 % time 531ps typ, 712ps min, 364ps max; typ from 0 V to 1.17 V
|   rising waveform, R_fixture 50.000, V_fixture 3.300: 20-80 % time 316ps typ, 360ps min, 238ps max; typ from 2.15 V to 3.3 V
|   falling waveform, R_fixture 50.000, V_fixture 3.300: 20-80 % time 888ps typ, 1.23ns min, 636ps max; typ from 3.3 V to 2.15 V
|   falling waveform, R_fixture 50.000, V_fixture 0.0: 20-80 % time 319ps typ, 372ps min, 254ps max; typ from 1.17 V to 0 V
[Pulldown]
|Voltage   I(typ)   I(min)   I(max)
-3.3V     -14.66mA   -8.951mA   -22.6mA
-900mV    -14.66mA   -8.951mA   -22.6mA
-500mV    -11.02mA   -7.807mA   -15.8mA
600mV     11.95mA    8.157mA    17.61mA
1.2V      19.4mA     13.27mA    28.41mA
1.9V      22.39mA    15.51mA    32.23mA
4V        24.55mA    17.73mA    34.86mA
4.5V      28.02mA    20.57mA    38.42mA
5.1V      36.45mA    26.6mA     51.27mA
5.6V      47.57mA    34.07mA    69.12mA
6.1V      62.73mA    43.93mA    93.72mA
6.6V      81.7mA     55.87mA    124.7mA
[Pullup]
|Voltage   I(typ)   I(min)   I(max)
-3.3V     50.71mA    34.33mA    84.23mA
-2.6V     50.71mA    34.33mA    84.09mA
-2.4V     49.45mA    34.33mA    80.61mA
-2.1V     45.03mA    32.7mA     72.27mA
-1.6V     35.33mA    26.42mA    55.44mA
-700mV    15.71mA    11.98mA    23.38mA
200mV     -4.043mA   -3.026mA   -6.275mA
800mV     -13.76mA   -10.18mA   -21.62mA
1.4V      -20.07mA   -14.6mA    -32.02mA
1.9V      -22.89mA   -16.38mA   -37.17mA
2.4V      -23.97mA   -16.98mA   -39.52mA
6.6V      -27.59mA   -19.35mA   -46.21mA
[GND_clamp]
|Voltage   I(typ)   I(min)   I(max)
-3.3V     -4.507A    -3.482A    -6.263A
-1.089V   -398.4mA   -420.6mA   -374.7mA
-1.022V   -290.7mA   -338.6mA   -230.6mA
-955mV    -191.4mA   -260.2mA   -120.1mA
-888mV    -107.5mA   -187mA     -73.7mA
-821mV    -53mA      -121.4mA   -59.85mA
-754mV    -31.41mA   -66.94mA   -47.47mA
-687mV    -21.17mA   -28.82mA   -34.25mA
-620mV    -13.21mA   -10.23mA   -22mA
-486mV    -2.63mA    -1.112mA   -4.479mA
-285mV    -80.91uA   -42.41uA   -152.3uA
6.6V      121.2uA    55.84uA    291.2uA
[POWER_clamp]
|Voltage   I(typ)   I(min)   I(max)
-3.3V     59.17mA    46.96mA    89.71mA
-1.993V   37.21mA    28.87mA    58.18mA
-1.926V   35.73mA    27.67mA    56.02mA
-1.591V   27.93mA    21.43mA    44.63mA
-1.189V   17.84mA    13.65mA    29.69mA
-1.122V   16.09mA    12.35mA    27.06mA
-988mV    12.53mA    9.74mA     21.66mA
-787mV    7.047mA    5.88mA     12.98mA
-586mV    1.736mA    2.238mA    3.233mA
-519mV    672uA      1.196mA    1.278mA
-452mV    189uA      428.3uA    309.6uA
3.3V      0A         0A         0A
[Ramp]
| variable   typ   min   max
dV/dt_r   0.703/0.532n   0.506/0.719n   1.059/0.365n
dV/dt_f   0.687/0.894n   0.481/1.230n   0.969/0.630n
R_load = 50.000
[Rising Waveform]
R_fixture= 50.000
V_fixture= 0.0
V_fixture_min= 0.0
V_fixture_max= 0.0
|time   V(typ)   V(min)   V(max)
0s        27.06nV    64.78nV    334.4nV
686ps     555uV      -1.879uV   21.47mV
767ps     -1.047mV   -1.879uV   207.2mV
983ps     -18.56mV   119.4uV    998.7mV
1.189ns   41.81mV    41.05uV    1.435V
1.663ns   758.2mV    -9.15mV    1.702V
1.956ns   990mV      68.94mV    1.739V
2.805ns   1.149V     674.3mV    1.762V
3.762ns   1.169V     820.9mV    1.764V
20ns      1.171V     842.7mV    1.765V
[Rising Waveform]
R_fixture= 50.000
V_fixture= 3.300
V_fixture_min= 3.140
V_fixture_max= 3.470
|time   V(typ)   V(min)   V(max)
0s        2.153V     2.336V     1.85V
489ps     2.153V     2.336V     1.864V
634ps     2.153V     2.336V     2.623V
799ps     2.156V     2.336V     3.166V
1.048ns   2.869V     2.337V     3.394V
1.258ns   3.122V     2.338V     3.432V
1.354ns   3.183V     2.478V     3.441V
1.655ns   3.259V     2.948V     3.456V
2.629ns   3.294V     3.124V     3.465V
20ns      3.297V     3.139V     3.465V
[Falling Waveform]
R_fixture= 50.000
V_fixture= 3.300
V_fixture_min= 3.140
V_fixture_max= 3.470
|time   V(typ)   V(min)   V(max)
0s        3.297V     3.139V     3.465V
657ps     3.297V     3.139V     3.49V
935ps     3.329V     3.139V     3.087V
1.186ns   3.294V     3.138V     2.547V
1.45ns    3.079V     3.144V     2.226V
1.726ns   2.797V     3.161V     2.04V
2.459ns   2.345V     2.929V     1.879V
3.32ns    2.192V     2.563V     1.853V
4.714ns   2.156V     2.372V     1.85V
20ns      2.153V     2.336V     1.85V
[Falling Waveform]
R_fixture= 50.000
V_fixture= 0.0
V_fixture_min= 0.0
V_fixture_max= 0.0
|time   V(typ)   V(min)   V(max)
0s        1.171V     842.7mV    1.765V
516ps     1.171V     842.6mV    1.749V
647ps     1.171V     842.7mV    985.1mV
857ps     1.171V     842.7mV    288.2mV
1.094ns   495.7mV    842.5mV    65.29mV
1.336ns   175.4mV    843.5mV    22.81mV
1.485ns   87.81mV    808.3mV    12.9mV
1.896ns   17.86mV    182.7mV    3.033mV
2.782ns   1.671mV    11.75mV    245.3uV
20ns      32.05nV    128nV      313.9nV
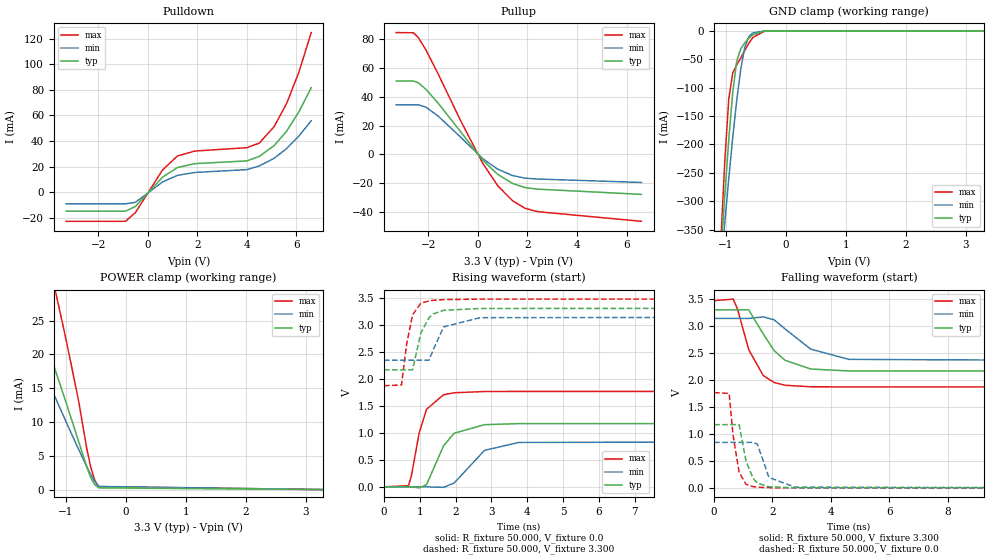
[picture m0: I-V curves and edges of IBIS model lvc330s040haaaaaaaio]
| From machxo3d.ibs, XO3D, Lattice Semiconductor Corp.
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|   Model lvc330s040haaaaaaaio
[Model] lvc330s040haaaaaaaio
Model_type I/O
Polarity   Non-Inverting
Enable   Active-Low
Vinl =  0.800V
Vinh =  2.000V
Vmeas =  1.650V
Cref =  0.0F
Rref =  1.000M
Vref =  0.0V
C_comp   4.200pF   3.800pF   7.500pF
[Temperature Range]   25.000   0.105k   -40.000
[Voltage Range]   3.300V   3.140V   3.470V
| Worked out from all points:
|   slope of the pulldown table from 0 to 0.495 V, typ, clamps not added: 48.6 ohm
|   slope of the pullup table from 0 to 0.495 V, typ, clamps not added: 53.4 ohm
|   GND clamp passes 1 mA (typ) near -0.43 V on its own axis
|   POWER clamp passes 1 mA (typ) near -0.53 V on its own axis
|   rising waveform, R_fixture 50.000, V_fixture 0.0: 20-80 % time 531ps typ, 712ps min, 364ps max; typ from 0 V to 1.17 V
|   rising waveform, R_fixture 50.000, V_fixture 3.300: 20-80 % time 314ps typ, 356ps min, 236ps max; typ from 2.16 V to 3.3 V
|   falling waveform, R_fixture 50.000, V_fixture 3.300: 20-80 % time 887ps typ, 1.24ns min, 634ps max; typ from 3.3 V to 2.16 V
|   falling waveform, R_fixture 50.000, V_fixture 0.0: 20-80 % time 319ps typ, 373ps min, 254ps max; typ from 1.17 V to 0 V
[Pulldown]
|Voltage   I(typ)   I(min)   I(max)
-3.3V     -14.66mA   -8.951mA   -22.6mA
-900mV    -14.66mA   -8.951mA   -22.6mA
-500mV    -11.02mA   -7.807mA   -15.8mA
600mV     11.95mA    8.157mA    17.61mA
1.2V      19.4mA     13.27mA    28.41mA
1.9V      22.39mA    15.51mA    32.23mA
4V        24.55mA    17.73mA    34.86mA
4.5V      28.02mA    20.57mA    38.42mA
5.1V      36.44mA    26.6mA     51.27mA
5.6V      47.57mA    34.07mA    69.12mA
6.1V      62.73mA    43.94mA    93.72mA
6.6V      81.69mA    55.88mA    124.7mA
[Pullup]
|Voltage   I(typ)   I(min)   I(max)
-3.3V     50.75mA    34.36mA    84.26mA
-2.6V     50.75mA    34.36mA    84.11mA
-2.4V     49.47mA    34.36mA    80.63mA
-2.1V     45.04mA    32.71mA    72.27mA
-1.6V     35.33mA    26.42mA    55.44mA
-700mV    15.71mA    11.98mA    23.38mA
200mV     -4.043mA   -3.026mA   -6.275mA
800mV     -13.76mA   -10.18mA   -21.62mA
1.4V      -20.07mA   -14.6mA    -32.02mA
1.9V      -22.89mA   -16.38mA   -37.17mA
2.4V      -23.97mA   -16.98mA   -39.52mA
6.6V      -27.59mA   -19.35mA   -46.21mA
[GND_clamp]
|Voltage   I(typ)   I(min)   I(max)
-3.3V     -4.507A    -3.482A    -6.263A
-1.089V   -398.4mA   -420.6mA   -374.7mA
-1.022V   -290.7mA   -338.6mA   -230.6mA
-955mV    -191.4mA   -260.2mA   -120.1mA
-888mV    -107.5mA   -187mA     -73.7mA
-821mV    -53mA      -121.4mA   -59.85mA
-754mV    -31.41mA   -66.94mA   -47.47mA
-687mV    -21.17mA   -28.82mA   -34.25mA
-620mV    -13.21mA   -10.23mA   -22mA
-553mV    -6.875mA   -3.578mA   -11.73mA
-352mV    -176.3uA   -89.98uA   -279uA
3.3V      50.87nA    0A         -26.43uA
[POWER_clamp]
|Voltage   I(typ)   I(min)   I(max)
-3.3V     62.1mA     51.02mA    92.7mA
-1.926V   36.35mA    28.59mA    56.55mA
-1.591V   28.28mA    21.98mA    45.01mA
-1.189V   18.03mA    13.9mA     29.96mA
-1.122V   16.26mA    12.55mA    27.31mA
-988mV    12.68mA    9.882mA    21.88mA
-787mV    7.154mA    5.963mA    13.15mA
-653mV    3.439mA    3.462mA    6.207mA
-586mV    1.819mA    2.29mA     3.395mA
-519mV    748.7uA    1.242mA    1.434mA
-452mV    255.4uA    468.1uA    442.9uA
3.3V      0A         0A         0A
[Ramp]
| variable   typ   min   max
dV/dt_r   0.703/0.532n   0.506/0.719n   1.059/0.365n
dV/dt_f   0.682/0.894n   0.480/1.224n   0.960/0.631n
R_load = 50.000
[Rising Waveform]
R_fixture= 50.000
V_fixture= 0.0
V_fixture_min= 0.0
V_fixture_max= 0.0
|time   V(typ)   V(min)   V(max)
0s        27.06nV    64.78nV    334.4nV
686ps     555uV      -1.899uV   21.47mV
767ps     -1.047mV   -1.899uV   207.2mV
983ps     -18.56mV   119.4uV    998.7mV
1.189ns   41.81mV    41.04uV    1.435V
1.663ns   758.2mV    -9.15mV    1.702V
1.956ns   990mV      68.94mV    1.739V
2.805ns   1.149V     674.3mV    1.762V
3.762ns   1.169V     820.9mV    1.764V
20ns      1.171V     842.7mV    1.765V
[Rising Waveform]
R_fixture= 50.000
V_fixture= 3.300
V_fixture_min= 3.140
V_fixture_max= 3.470
|time   V(typ)   V(min)   V(max)
0s        2.163V     2.341V     1.87V
489ps     2.163V     2.341V     1.883V
636ps     2.163V     2.341V     2.65V
799ps     2.165V     2.341V     3.179V
1.028ns   2.842V     2.341V     3.394V
1.26ns    3.129V     2.343V     3.438V
1.37ns    3.195V     2.526V     3.448V
1.666ns   3.263V     2.957V     3.461V
2.68ns    3.297V     3.127V     3.47V
20ns      3.3V       3.14V      3.47V
[Falling Waveform]
R_fixture= 50.000
V_fixture= 3.300
V_fixture_min= 3.140
V_fixture_max= 3.470
|time   V(typ)   V(min)   V(max)
0s        3.3V       3.14V      3.47V
659ps     3.299V     3.14V      3.497V
811ps     3.299V     3.14V      3.296V
1.186ns   3.298V     3.139V     2.562V
1.68ns    2.856V     3.168V     2.082V
2.055ns   2.543V     3.114V     1.953V
2.433ns   2.363V     2.944V     1.901V
3.311ns   2.202V     2.57V      1.873V
4.617ns   2.166V     2.381V     1.87V
20ns      2.163V     2.341V     1.87V
[Falling Waveform]
R_fixture= 50.000
V_fixture= 0.0
V_fixture_min= 0.0
V_fixture_max= 0.0
|time   V(typ)   V(min)   V(max)
0s        1.171V     842.7mV    1.765V
516ps     1.171V     842.6mV    1.749V
647ps     1.171V     842.7mV    985.1mV
857ps     1.171V     842.7mV    288.2mV
1.094ns   495.7mV    842.5mV    65.29mV
1.336ns   175.4mV    843.5mV    22.81mV
1.485ns   87.81mV    808.3mV    12.9mV
1.881ns   18.74mV    191.9mV    3.431mV
2.782ns   1.671mV    11.75mV    256.6uV
20ns      32.05nV    128nV      313.9nV
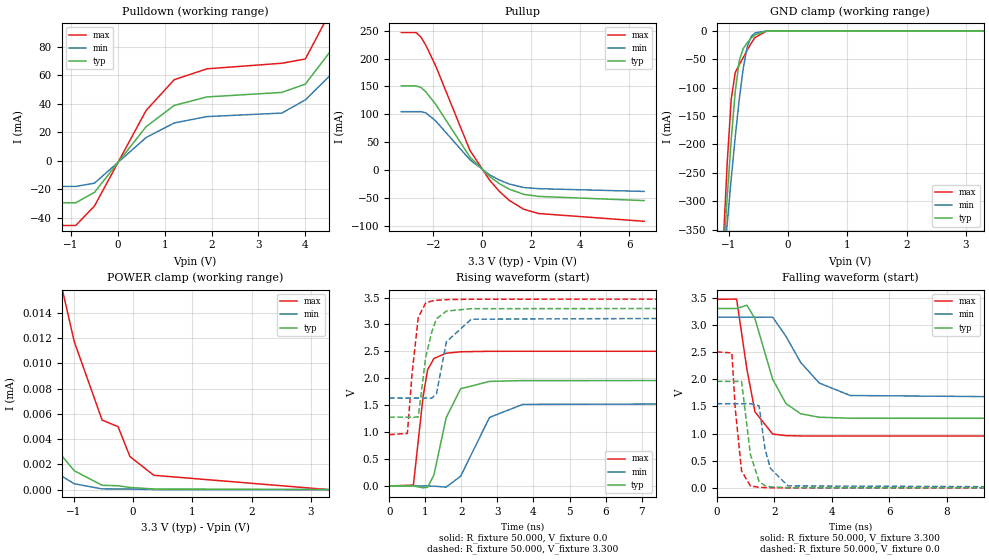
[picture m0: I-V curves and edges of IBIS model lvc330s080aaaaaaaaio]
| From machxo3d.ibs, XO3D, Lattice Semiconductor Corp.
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|   Model lvc330s080aaaaaaaaio
[Model] lvc330s080aaaaaaaaio
Model_type I/O
Polarity   Non-Inverting
Enable   Active-Low
Vinl =  0.800V
Vinh =  2.000V
Vmeas =  1.650V
Cref =  0.0F
Rref =  1.000M
Vref =  0.0V
C_comp   4.200pF   3.800pF   7.500pF
[Temperature Range]   25.000   0.105k   -40.000
[Voltage Range]   3.300V   3.140V   3.470V
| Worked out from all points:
|   slope of the pulldown table from 0 to 0.495 V, typ, clamps not added: 24.3 ohm
|   slope of the pullup table from 0 to 0.495 V, typ, clamps not added: 26.7 ohm
|   GND clamp passes 1 mA (typ) near -0.43 V on its own axis
|   rising waveform, R_fixture 50.000, V_fixture 0.0: 20-80 % time 423ps typ, 673ps min, 235ps max; typ from 0 V to 1.96 V
|   rising waveform, R_fixture 50.000, V_fixture 3.300: 20-80 % time 301ps typ, 346ps min, 210ps max; typ from 1.28 V to 3.3 V
|   falling waveform, R_fixture 50.000, V_fixture 3.300: 20-80 % time 786ps typ, 1.19ns min, 450ps max; typ from 3.3 V to 1.28 V
|   falling waveform, R_fixture 50.000, V_fixture 0.0: 20-80 % time 315ps typ, 367ps min, 235ps max; typ from 1.96 V to 0 V
[Pulldown]
|Voltage   I(typ)   I(min)   I(max)
-3.3V     -29.32mA   -17.9mA    -45.21mA
-900mV    -29.32mA   -17.9mA    -45.21mA
-500mV    -22.04mA   -15.61mA   -31.59mA
600mV     23.9mA     16.31mA    35.23mA
1.2V      38.8mA     26.54mA    56.81mA
1.9V      44.78mA    31.02mA    64.46mA
3.5V      47.95mA    33.48mA    68.37mA
4V        53.77mA    42.73mA    71.35mA
4.7V      83.76mA    65.33mA    114.8mA
5.3V      118.2mA    90.38mA    168.1mA
5.9V      161.6mA    120.5mA    237.1mA
6.6V      222mA      159.5mA    335.5mA
[Pullup]
|Voltage   I(typ)   I(min)   I(max)
-3.3V     151mA      104.7mA    246.9mA
-2.7V     151mA      104.7mA    246.9mA
-2.5V     148.4mA    104.7mA    238.8mA
-2.3V     140.2mA    102.5mA    224mA
-1.9V     118mA      88.17mA    187mA
-500mV    22.91mA    18.07mA    34.77mA
300mV     -11.82mA   -8.831mA   -18.38mA
700mV     -24.77mA   -18.36mA   -38.83mA
1.1V      -34.65mA   -25.44mA   -54.83mA
1.7V      -44.02mA   -31.73mA   -70.96mA
2.3V      -47.65mA   -33.78mA   -78.43mA
6.6V      -55.19mA   -38.7mA    -92.41mA
[GND_clamp]
|Voltage   I(typ)   I(min)   I(max)
-3.3V     -4.507A    -3.482A    -6.263A
-1.089V   -398.4mA   -420.6mA   -374.7mA
-1.022V   -290.7mA   -338.6mA   -230.6mA
-955mV    -191.3mA   -260.2mA   -120mA
-888mV    -107.5mA   -187mA     -73.64mA
-821mV    -52.96mA   -121.4mA   -59.79mA
-754mV    -31.36mA   -66.92mA   -47.4mA
-687mV    -21.12mA   -28.79mA   -34.18mA
-620mV    -13.16mA   -10.19mA   -21.93mA
-553mV    -6.814mA   -3.53mA    -11.64mA
-352mV    -96.36uA   -46.21uA   -149.8uA
3.3V      0A         0A         0A
[POWER_clamp]
|Voltage   I(typ)   I(min)   I(max)
-3.3V     732.2uA    455.9uA    1.265mA
-2.663V   69.44uA    15.46uA    306.8uA
-2.529V   27.69uA    10.95uA    164.1uA
-2.328V   15.69uA    8.498uA    64.68uA
-1.725V   7.348uA    3.693uA    30.69uA
-1.189V   2.632uA    1.04uA     15.85uA
-988mV    1.494uA    463.1nA    11.72uA
-519mV    342.8nA    54.78nA    5.51uA
-251mV    305.1nA    47.66nA    4.994uA
-50mV     169nA      47.66nA    2.616uA
352mV     50.67nA    4.149nA    1.135uA
3.3V      0A         0A         0A
[Ramp]
| variable   typ   min   max
dV/dt_r   1.175/0.423n   0.929/0.671n   1.501/0.235n
dV/dt_f   1.213/0.783n   0.904/1.195n   1.510/0.451n
R_load = 50.000
[Rising Waveform]
R_fixture= 50.000
V_fixture= 0.0
V_fixture_min= 0.0
V_fixture_max= 0.0
|time   V(typ)   V(min)   V(max)
0s        17.95nV    45.29nV    212.7nV
671ps     368.5uV    -3.224uV   16.19mV
941ps     -35.03mV   21.48uV    1.669V
1.066ns   -23.85mV   417.5uV    2.16V
1.24ns    204.1mV    -3.742mV   2.368V
1.578ns   1.264V     -21.15mV   2.465V
1.982ns   1.806V     181.8mV    2.492V
2.781ns   1.942V     1.273V     2.501V
3.702ns   1.957V     1.515V     2.502V
20ns      1.959V     1.548V     2.502V
[Rising Waveform]
R_fixture= 50.000
V_fixture= 3.300
V_fixture_min= 3.140
V_fixture_max= 3.470
|time   V(typ)   V(min)   V(max)
0s        1.278V     1.633V     953.3mV
504ps     1.278V     1.633V     975.9mV
634ps     1.278V     1.633V     2.086V
806ps     1.281V     1.633V     3.131V
1.011ns   2.388V     1.633V     3.398V
1.183ns   2.866V     1.631V     3.435V
1.31ns    3.104V     1.711V     3.448V
1.586ns   3.248V     2.678V     3.461V
2.276ns   3.293V     3.098V     3.469V
20ns      3.3V       3.14V      3.47V
[Falling Waveform]
R_fixture= 50.000
V_fixture= 3.300
V_fixture_min= 3.140
V_fixture_max= 3.470
|time   V(typ)   V(min)   V(max)
0s        3.3V       3.14V      3.47V
692ps     3.299V     3.14V      3.472V
1.051ns   3.36V      3.14V      2.175V
1.33ns    3.11V      3.139V     1.399V
1.943ns   1.999V     3.14V      989.6mV
2.403ns   1.552V     2.79V      961.4mV
2.918ns   1.363V     2.306V     954.9mV
3.563ns   1.299V     1.928V     953.5mV
4.638ns   1.281V     1.699V     953.2mV
20ns      1.278V     1.633V     953.2mV
[Falling Waveform]
R_fixture= 50.000
V_fixture= 0.0
V_fixture_min= 0.0
V_fixture_max= 0.0
|time   V(typ)   V(min)   V(max)
0s        1.959V     1.548V     2.502V
526ps     1.959V     1.548V     2.483V
645ps     1.959V     1.548V     1.451V
864ps     1.957V     1.548V     311.4mV
1.171ns   612.4mV    1.548V     34.94mV
1.473ns   116.5mV    1.508V     10.28mV
1.679ns   40.08mV    708.8mV    4.964mV
1.869ns   19.48mV    354.8mV    2.481mV
2.477ns   3.31mV     36.1mV     396.6uV
20ns      78.15nV    117nV      236.2nV
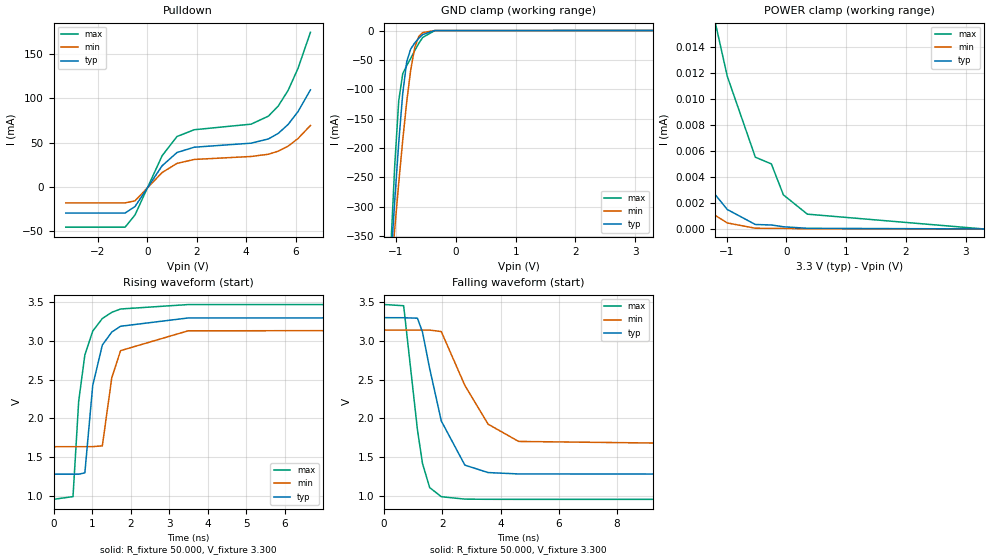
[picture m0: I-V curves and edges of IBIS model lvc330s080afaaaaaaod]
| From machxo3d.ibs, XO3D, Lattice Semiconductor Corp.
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|   Model lvc330s080afaaaaaaod
[Model] lvc330s080afaaaaaaod
Model_type I/O_open_drain
Polarity   Non-Inverting
Enable   Active-Low
Vinl =  0.800V
Vinh =  2.000V
Vmeas =  1.650V
Cref =  0.0F
Rref = 10.00k
Vref = 3.30V
C_comp   4.200pF   3.800pF   7.500pF
[Temperature Range]   25.000   0.105k   -40.000
[Voltage Range]   3.300V   3.140V   3.470V
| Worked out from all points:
|   slope of the pulldown table from 0 to 0.495 V, typ, clamps not added: 24.3 ohm
|   GND clamp passes 1 mA (typ) near -0.43 V on its own axis
|   rising waveform, R_fixture 50.000, V_fixture 3.300: 20-80 % time 329ps typ, 334ps min, 330ps max; typ from 1.28 V to 3.3 V
|   falling waveform, R_fixture 50.000, V_fixture 3.300: 20-80 % time 789ps typ, 1.19ns min, 453ps max; typ from 3.3 V to 1.28 V
[Pulldown]
|Voltage   I(typ)   I(min)   I(max)
-3.3V     -29.32mA   -17.9mA    -45.21mA
-900mV    -29.32mA   -17.9mA    -45.21mA
-500mV    -22.04mA   -15.61mA   -31.59mA
600mV     23.9mA     16.31mA    35.23mA
1.2V      38.8mA     26.54mA    56.81mA
1.9V      44.78mA    31.02mA    64.46mA
4.2V      49.32mA    34.33mA    70.73mA
4.9V      54.1mA     36.88mA    79.76mA
5.3V      60.39mA    40.34mA    91.21mA
5.7V      70.49mA    46.08mA    108.9mA
6.1V      84.99mA    54.58mA    133.7mA
6.6V      109.3mA    69.26mA    174.1mA
[GND_clamp]
|Voltage   I(typ)   I(min)   I(max)
-3.3V     -4.507A    -3.482A    -6.263A
-1.089V   -398.4mA   -420.6mA   -374.7mA
-1.022V   -290.7mA   -338.6mA   -230.6mA
-955mV    -191.3mA   -260.2mA   -120mA
-888mV    -107.5mA   -187mA     -73.64mA
-821mV    -52.96mA   -121.4mA   -59.79mA
-754mV    -31.36mA   -66.92mA   -47.4mA
-687mV    -21.12mA   -28.79mA   -34.18mA
-620mV    -13.16mA   -10.19mA   -21.93mA
-553mV    -6.814mA   -3.53mA    -11.64mA
-352mV    -96.36uA   -46.21uA   -149.8uA
3.3V      0A         0A         0A
[POWER_clamp]
|Voltage   I(typ)   I(min)   I(max)
-3.3V     732.2uA    455.9uA    1.265mA
-2.663V   69.44uA    15.46uA    306.8uA
-2.529V   27.69uA    10.95uA    164.1uA
-2.328V   15.69uA    8.498uA    64.68uA
-1.725V   7.348uA    3.693uA    30.69uA
-1.189V   2.631uA    1.04uA     15.85uA
-988mV    1.494uA    463.1nA    11.72uA
-519mV    342.8nA    54.77nA    5.51uA
-251mV    305nA      47.65nA    4.994uA
-50mV     169nA      47.65nA    2.616uA
352mV     50.67nA    4.149nA    1.135uA
3.3V      0A         0A         0A
[Ramp]
| variable   typ   min   max
dV/dt_r   1.213/0.328n   0.904/0.332n   1.510/0.329n
dV/dt_f   1.213/0.786n   0.904/1.196n   1.510/0.454n
R_load = 50.000
[Rising Waveform]
R_fixture= 50.000
V_fixture= 3.300
V_fixture_min= 3.140
V_fixture_max= 3.470
|time   V(typ)   V(min)   V(max)
0s        1.278V     1.633V     953.3mV
505ps     1.278V     1.633V     988.5mV
652ps     1.278V     1.633V     2.219V
812ps     1.295V     1.633V     2.818V
1.016ns   2.424V     1.634V     3.126V
1.265ns   2.946V     1.644V     3.289V
1.51ns    3.114V     2.524V     3.369V
1.738ns   3.189V     2.874V     3.412V
3.488ns   3.296V     3.13V      3.469V
20ns      3.3V       3.14V      3.47V
[Falling Waveform]
R_fixture= 50.000
V_fixture= 3.300
V_fixture_min= 3.140
V_fixture_max= 3.470
|time   V(typ)   V(min)   V(max)
0s        3.3V       3.14V      3.47V
673ps     3.299V     3.14V      3.454V
1.146ns   3.293V     3.139V     1.853V
1.32ns    3.113V     3.139V     1.416V
1.566ns   2.643V     3.14V      1.105V
1.966ns   1.965V     3.12V      986.9mV
2.775ns   1.395V     2.425V     955.8mV
3.574ns   1.299V     1.924V     953.5mV
4.622ns   1.281V     1.701V     953.2mV
20ns      1.278V     1.633V     953.2mV
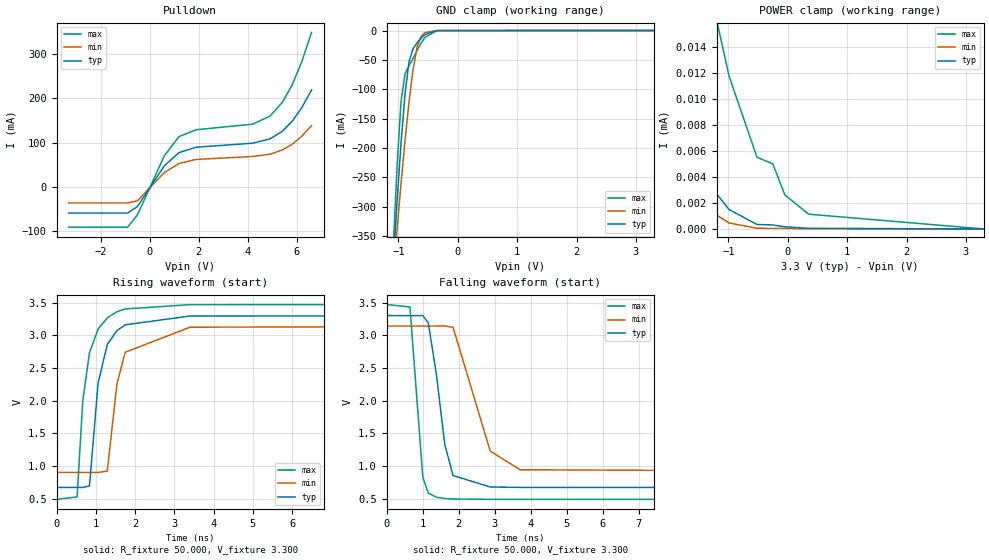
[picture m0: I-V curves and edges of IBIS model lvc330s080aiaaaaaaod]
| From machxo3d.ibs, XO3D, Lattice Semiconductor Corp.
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|   Model lvc330s080aiaaaaaaod
[Model] lvc330s080aiaaaaaaod
Model_type I/O_open_drain
Polarity   Non-Inverting
Enable   Active-Low
Vinl =  0.800V
Vinh =  2.000V
Vmeas =  1.650V
Cref =  0.0F
Rref = 10.00k
Vref = 3.30V
C_comp   4.200pF   3.800pF   7.500pF
[Temperature Range]   25.000   0.105k   -40.000
[Voltage Range]   3.300V   3.140V   3.470V
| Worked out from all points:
|   slope of the pulldown table from 0 to 0.495 V, typ, clamps not added: 12.2 ohm
|   GND clamp passes 1 mA (typ) near -0.43 V on its own axis
|   rising waveform, R_fixture 50.000, V_fixture 3.300: 20-80 % time 324ps typ, 327ps min, 329ps max; typ from 0.669 V to 3.3 V
|   falling waveform, R_fixture 50.000, V_fixture 3.300: 20-80 % time 379ps typ, 657ps min, 212ps max; typ from 3.3 V to 0.669 V
[Pulldown]
|Voltage   I(typ)   I(min)   I(max)
-3.3V     -58.64mA   -35.81mA   -90.41mA
-900mV    -58.64mA   -35.81mA   -90.41mA
-500mV    -44.08mA   -31.23mA   -63.19mA
600mV     47.81mA    32.63mA    70.46mA
1.2V      77.59mA    53.08mA    113.6mA
1.9V      89.57mA    62.04mA    128.9mA
4.2V      98.64mA    68.65mA    141.5mA
4.9V      108.2mA    73.77mA    159.5mA
5.4V      125.1mA    83.07mA    190mA
5.8V      147.4mA    95.86mA    228.9mA
6.2V      178.7mA    114.3mA    281.9mA
6.6V      218.6mA    138.5mA    348.2mA
[GND_clamp]
|Voltage   I(typ)   I(min)   I(max)
-3.3V     -4.507A    -3.482A    -6.263A
-1.089V   -398.4mA   -420.6mA   -374.7mA
-1.022V   -290.7mA   -338.6mA   -230.6mA
-955mV    -191.3mA   -260.2mA   -120mA
-888mV    -107.5mA   -187mA     -73.64mA
-821mV    -52.96mA   -121.4mA   -59.79mA
-754mV    -31.36mA   -66.92mA   -47.4mA
-687mV    -21.12mA   -28.79mA   -34.18mA
-620mV    -13.16mA   -10.19mA   -21.93mA
-553mV    -6.814mA   -3.53mA    -11.64mA
-352mV    -96.36uA   -46.21uA   -149.8uA
3.3V      0A         0A         0A
[POWER_clamp]
|Voltage   I(typ)   I(min)   I(max)
-3.3V     732.2uA    455.9uA    1.265mA
-2.663V   69.44uA    15.46uA    306.8uA
-2.529V   27.69uA    10.95uA    164.1uA
-2.328V   15.69uA    8.498uA    64.68uA
-1.725V   7.348uA    3.693uA    30.69uA
-1.189V   2.632uA    1.04uA     15.85uA
-988mV    1.494uA    463.1nA    11.72uA
-519mV    342.8nA    54.78nA    5.51uA
-251mV    305.1nA    47.65nA    4.994uA
-50mV     169nA      47.65nA    2.616uA
352mV     50.67nA    4.149nA    1.135uA
3.3V      0A         0A         0A
[Ramp]
| variable   typ   min   max
dV/dt_r   1.578/0.325n   1.344/0.325n   1.789/0.327n
dV/dt_f   1.578/0.379n   1.345/0.656n   1.789/0.212n
R_load = 50.000
[Rising Waveform]
R_fixture= 50.000
V_fixture= 3.300
V_fixture_min= 3.140
V_fixture_max= 3.470
|time   V(typ)   V(min)   V(max)
0s        669.4mV    899.2mV    487.7mV
524ps     669.4mV    899.2mV    524.3mV
668ps     669.8mV    899.2mV    1.992V
839ps     693.4mV    899.2mV    2.733V
1.059ns   2.268V     899.3mV    3.095V
1.292ns   2.858V     920.4mV    3.266V
1.538ns   3.07V      2.252V     3.359V
1.749ns   3.159V     2.739V     3.402V
3.402ns   3.294V     3.123V     3.468V
20ns      3.3V       3.14V      3.47V
[Falling Waveform]
R_fixture= 50.000
V_fixture= 3.300
V_fixture_min= 3.140
V_fixture_max= 3.470
|time   V(typ)   V(min)   V(max)
0s        3.3V       3.14V      3.47V
650ps     3.299V     3.14V      3.432V
1.007ns   3.301V     3.14V      824.3mV
1.161ns   3.185V     3.139V     581.4mV
1.391ns   2.371V     3.14V      518.9mV
1.615ns   1.332V     3.141V     499.9mV
1.846ns   852.1mV    3.121V     492.6mV
2.879ns   676.6mV    1.225V     487.7mV
3.708ns   670.2mV    940.6mV    487.5mV
20ns      669.4mV    899.1mV    487.5mV
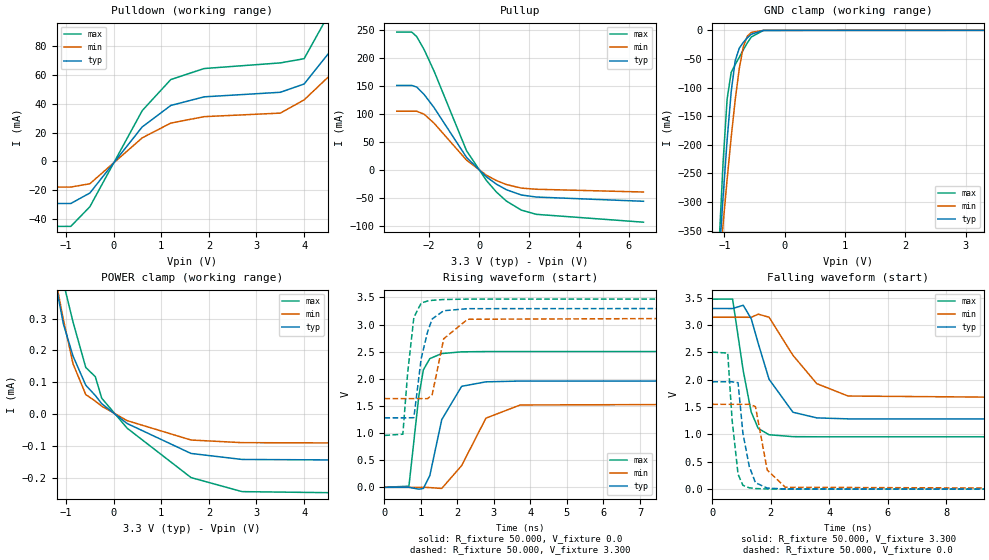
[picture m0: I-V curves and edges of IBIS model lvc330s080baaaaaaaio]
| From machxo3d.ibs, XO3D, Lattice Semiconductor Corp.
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|   Model lvc330s080baaaaaaaio
[Model] lvc330s080baaaaaaaio
Model_type I/O
Polarity   Non-Inverting
Enable   Active-Low
Vinl =  0.800V
Vinh =  2.000V
Vmeas =  1.650V
Cref =  0.0F
Rref =  1.000M
Vref =  0.0V
C_comp   4.200pF   3.800pF   7.500pF
[Temperature Range]   25.000   0.105k   -40.000
[Voltage Range]   3.300V   3.140V   3.470V
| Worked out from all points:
|   slope of the pulldown table from 0 to 0.495 V, typ, clamps not added: 24.3 ohm
|   slope of the pullup table from 0 to 0.495 V, typ, clamps not added: 26.7 ohm
|   GND clamp passes 1 mA (typ) near -0.43 V on its own axis
|   POWER clamp passes 1 mA (typ) near -1.85 V on its own axis
|   rising waveform, R_fixture 50.000, V_fixture 0.0: 20-80 % time 423ps typ, 672ps min, 236ps max; typ from 0.002 V to 1.96 V
|   rising waveform, R_fixture 50.000, V_fixture 3.300: 20-80 % time 300ps typ, 346ps min, 209ps max; typ from 1.28 V to 3.3 V
|   falling waveform, R_fixture 50.000, V_fixture 3.300: 20-80 % time 792ps typ, 1.2ns min, 452ps max; typ from 3.3 V to 1.28 V
|   falling waveform, R_fixture 50.000, V_fixture 0.0: 20-80 % time 317ps typ, 369ps min, 236ps max; typ from 1.96 V to 0.002 V
[Pulldown]
|Voltage   I(typ)   I(min)   I(max)
-3.3V     -29.32mA   -17.9mA    -45.21mA
-900mV    -29.32mA   -17.9mA    -45.21mA
-500mV    -22.04mA   -15.61mA   -31.59mA
600mV     23.9mA     16.31mA    35.23mA
1.2V      38.8mA     26.54mA    56.81mA
1.9V      44.78mA    31.02mA    64.46mA
3.5V      47.95mA    33.48mA    68.37mA
4V        53.7mA     42.66mA    71.29mA
4.6V      78.57mA    61.48mA    107.1mA
5.3V      117.8mA    90.43mA    167.3mA
5.9V      161.4mA    121.1mA    236.3mA
6.6V      221.9mA    162.1mA    331.9mA
[Pullup]
|Voltage   I(typ)   I(min)   I(max)
-3.3V     151mA      105.1mA    246mA
-2.7V     151mA      105.1mA    246mA
-2.5V     148.2mA    105.1mA    238mA
-2.2V     134.8mA    99.77mA    214.6mA
-1.8V     111.3mA    83.67mA    176.1mA
-500mV    22.89mA    18.05mA    34.72mA
300mV     -11.82mA   -8.831mA   -18.38mA
700mV     -24.77mA   -18.36mA   -38.83mA
1.1V      -34.65mA   -25.44mA   -54.83mA
1.7V      -44.02mA   -31.73mA   -70.96mA
2.3V      -47.65mA   -33.78mA   -78.43mA
6.6V      -55.19mA   -38.7mA    -92.41mA
[GND_clamp]
|Voltage   I(typ)   I(min)   I(max)
-3.3V     -4.506A    -3.482A    -6.262A
-1.089V   -398.3mA   -420.5mA   -374.5mA
-1.022V   -290.6mA   -338.5mA   -230.4mA
-955mV    -191.2mA   -260.1mA   -119.8mA
-888mV    -107.4mA   -186.9mA   -73.47mA
-821mV    -52.87mA   -121.3mA   -59.62mA
-754mV    -31.28mA   -66.86mA   -47.24mA
-687mV    -21.04mA   -28.74mA   -34.02mA
-620mV    -13.09mA   -10.15mA   -21.79mA
-553mV    -6.755mA   -3.505mA   -11.52mA
-352mV    -90.18uA   -45.39uA   -119.9uA
3.3V      0A         0A         0A
[POWER_clamp]
|Voltage   I(typ)   I(min)   I(max)
-3.3V     3.967mA    2.512mA    11.53mA
-1.323V   507.3uA    506.4uA    605.6uA
-1.189V   387.7uA    399.8uA    501.1uA
-1.055V   282.8uA    296.7uA    413.8uA
-854mV    182.6uA    158.2uA    289.7uA
-586mV    90.73uA    61.33uA    146.6uA
-385mV    58.36uA    40.66uA    117.5uA
-251mV    32.53uA    24.74uA    49.87uA
285mV     -29.95uA   -20.85uA   -44.72uA
1.625V    -124uA     -81.72uA   -199.9uA
2.697V    -142.9uA   -90.03uA   -244.1uA
6.6V      -145.9uA   -91.75uA   -251.2uA
[Ramp]
| variable   typ   min   max
dV/dt_r   1.176/0.423n   0.930/0.671n   1.501/0.235n
dV/dt_f   1.211/0.786n   0.902/1.193n   1.507/0.453n
R_load = 50.000
[Rising Waveform]
R_fixture= 50.000
V_fixture= 0.0
V_fixture_min= 0.0
V_fixture_max= 0.0
|time   V(typ)   V(min)   V(max)
0s        2.128mV    1.725mV    2.736mV
671ps     2.486mV    1.72mV     23.2mV
942ps     -31.71mV   1.797mV    1.683V
1.067ns   -18.81mV   2.129mV    2.167V
1.243ns   217.7mV    -2.538mV   2.373V
1.57ns    1.249V     -18.7mV    2.466V
2.115ns   1.863V     402.4mV    2.498V
2.78ns    1.945V     1.276V     2.503V
3.718ns   1.96V      1.519V     2.504V
20ns      1.962V     1.551V     2.504V
[Rising Waveform]
R_fixture= 50.000
V_fixture= 3.300
V_fixture_min= 3.140
V_fixture_max= 3.470
|time   V(typ)   V(min)   V(max)
0s        1.282V     1.637V     957.6mV
504ps     1.282V     1.637V     980.8mV
635ps     1.282V     1.637V     2.101V
806ps     1.285V     1.637V     3.134V
1.007ns   2.376V     1.637V     3.397V
1.183ns   2.868V     1.634V     3.435V
1.31ns    3.105V     1.714V     3.447V
1.624ns   3.255V     2.739V     3.462V
2.28ns    3.293V     3.098V     3.469V
20ns      3.3V       3.14V      3.47V
[Falling Waveform]
R_fixture= 50.000
V_fixture= 3.300
V_fixture_min= 3.140
V_fixture_max= 3.470
|time   V(typ)   V(min)   V(max)
0s        3.3V       3.14V      3.47V
692ps     3.299V     3.14V      3.472V
1.055ns   3.359V     3.14V      2.165V
1.328ns   3.114V     3.139V     1.411V
1.568ns   2.665V     3.196V     1.111V
1.938ns   2.01V      3.141V     995.3mV
2.756ns   1.406V     2.446V     960.4mV
3.572ns   1.303V     1.928V     957.9mV
4.642ns   1.285V     1.702V     957.6mV
20ns      1.282V     1.637V     957.6mV
[Falling Waveform]
R_fixture= 50.000
V_fixture= 0.0
V_fixture_min= 0.0
V_fixture_max= 0.0
|time   V(typ)   V(min)   V(max)
0s        1.962V     1.551V     2.504V
526ps     1.962V     1.551V     2.486V
674ps     1.962V     1.551V     1.272V
879ps     1.945V     1.551V     273.9mV
1.045ns   1.024V     1.551V     71.83mV
1.261ns   420.3mV    1.551V     26.5mV
1.474ns   119.9mV    1.509V     12.92mV
1.878ns   21.27mV    349.2mV    5.185mV
2.498ns   5.348mV    36.16mV    3.123mV
20ns      2.128mV    1.725mV    2.736mV
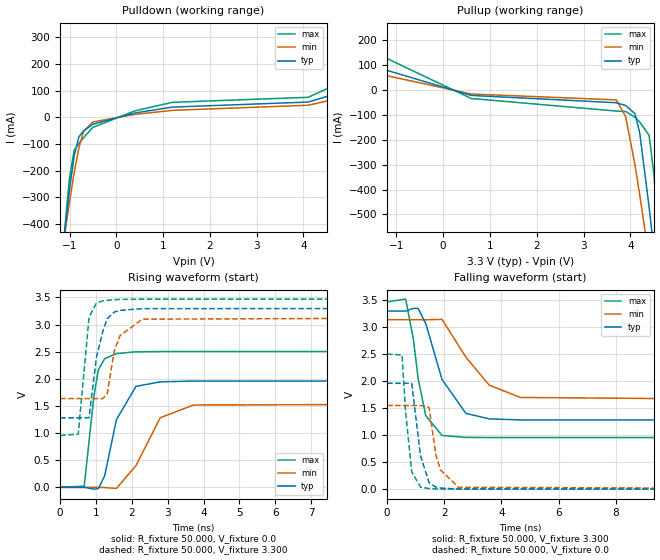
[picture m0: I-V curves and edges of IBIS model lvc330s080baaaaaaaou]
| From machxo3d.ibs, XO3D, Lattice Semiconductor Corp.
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|   Model lvc330s080baaaaaaaou
[Model] lvc330s080baaaaaaaou
Model_type Output
Polarity   Non-Inverting
Enable   Active-High
Vmeas =  1.650V
Cref =  0.0F
Rref =  1.000M
Vref =  0.0V
C_comp   4.200pF   3.800pF   7.500pF
[Temperature Range]   25.000   0.105k   -40.000
[Voltage Range]   3.300V   3.140V   3.470V
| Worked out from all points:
|   slope of the pulldown table from 0 to 0.495 V, typ, clamps not added: 24.3 ohm
|   slope of the pullup table from 0 to 0.495 V, typ, clamps not added: 26.6 ohm
|   rising waveform, R_fixture 50.000, V_fixture 0.0: 20-80 % time 423ps typ, 674ps min, 235ps max; typ from 0.002 V to 1.96 V
|   rising waveform, R_fixture 50.000, V_fixture 3.300: 20-80 % time 300ps typ, 347ps min, 209ps max; typ from 1.28 V to 3.3 V
|   falling waveform, R_fixture 50.000, V_fixture 3.300: 20-80 % time 786ps typ, 1.19ns min, 453ps max; typ from 3.3 V to 1.28 V
|   falling waveform, R_fixture 50.000, V_fixture 0.0: 20-80 % time 317ps typ, 370ps min, 236ps max; typ from 1.96 V to 0.002 V
[Pulldown]
|Voltage   I(typ)   I(min)   I(max)
-3.3V     -4.507A    -3.482A    -6.263A
-1.1V     -423.4mA   -437.5mA   -416.7mA
-1V       -269.7mA   -316.9mA   -225.2mA
-900mV    -144.5mA   -206.8mA   -123.1mA
-800mV    -72.93mA   -115.2mA   -98.46mA
-700mV    -50.75mA   -52.06mA   -75.94mA
-500mV    -25.39mA   -17.08mA   -37.33mA
400mV     16.79mA    11.47mA    24.72mA
1.2V      38.66mA    26.45mA    56.57mA
4.1V      57.51mA    45.64mA    75.36mA
5.4V      125.6mA    96.49mA    179mA
6.6V      225.7mA    164.9mA    339mA
[Pullup]
|Voltage   I(typ)   I(min)   I(max)
-3.3V     152.9mA    106.6mA    248.9mA
-2.4V     145.9mA    106.3mA    233.1mA
600mV     -21.89mA   -16.25mA   -34.23mA
3.7V      -51.26mA   -39.86mA   -84.66mA
3.9V      -62.3mA    -107.4mA   -86.52mA
4.1V      -95.17mA   -302.3mA   -109.5mA
4.2V      -172.6mA   -421.2mA   -128.8mA
4.4V      -468.9mA   -676.6mA   -181.9mA
4.5V      -639.3mA   -809mA     -333.7mA
4.6V      -815.4mA   -943.4mA   -557.7mA
4.7V      -994.9mA   -1.079A    -803mA
6.6V      -4.562A    -3.748A    -5.893A
[Ramp]
| variable   typ   min   max
dV/dt_r   1.176/0.423n   0.930/0.671n   1.501/0.235n
dV/dt_f   1.211/0.786n   0.902/1.193n   1.507/0.453n
R_load = 50.000
[Rising Waveform]
R_fixture= 50.000
V_fixture= 0.0
V_fixture_min= 0.0
V_fixture_max= 0.0
|time   V(typ)   V(min)   V(max)
0s        2.128mV    1.725mV    2.736mV
671ps     2.476mV    1.719mV    23.2mV
943ps     -31.62mV   1.789mV    1.689V
1.067ns   -18.81mV   2.128mV    2.167V
1.241ns   212.6mV    -2.271mV   2.372V
1.57ns    1.249V     -18.77mV   2.466V
2.115ns   1.862V     402.4mV    2.498V
2.792ns   1.945V     1.284V     2.503V
3.72ns    1.96V      1.519V     2.504V
20ns      1.962V     1.551V     2.504V
[Rising Waveform]
R_fixture= 50.000
V_fixture= 3.300
V_fixture_min= 3.140
V_fixture_max= 3.470
|time   V(typ)   V(min)   V(max)
0s        1.282V     1.637V     957.6mV
504ps     1.282V     1.637V     980.8mV
806ps     1.285V     1.637V     3.134V
1.012ns   2.396V     1.637V     3.399V
1.182ns   2.856V     1.634V     3.435V
1.309ns   3.104V     1.712V     3.448V
1.512ns   3.232V     2.52V      3.459V
1.67ns    3.262V     2.796V     3.463V
2.291ns   3.293V     3.1V       3.469V
20ns      3.3V       3.14V      3.47V
[Falling Waveform]
R_fixture= 50.000
V_fixture= 3.300
V_fixture_min= 3.140
V_fixture_max= 3.470
|time   V(typ)   V(min)   V(max)
0s        3.3V       3.14V      3.47V
653ps     3.299V     3.14V      3.522V
922ps     3.35V      3.14V      2.776V
1.088ns   3.35V      3.14V      2.051V
1.355ns   3.068V     3.138V     1.361V
1.921ns   2.034V     3.146V     996.7mV
2.756ns   1.406V     2.446V     960.4mV
3.572ns   1.303V     1.928V     957.9mV
4.662ns   1.284V     1.7V       957.6mV
20ns      1.282V     1.637V     957.5mV
[Falling Waveform]
R_fixture= 50.000
V_fixture= 0.0
V_fixture_min= 0.0
V_fixture_max= 0.0
|time   V(typ)   V(min)   V(max)
0s        1.962V     1.551V     2.504V
526ps     1.962V     1.551V     2.486V
645ps     1.962V     1.551V     1.457V
864ps     1.96V      1.551V     319.2mV
1.173ns   614.3mV    1.551V     38.15mV
1.471ns   121.4mV    1.515V     13.3mV
1.707ns   38.53mV    637.4mV    6.972mV
1.869ns   22.4mV     359.2mV    5.036mV
2.499ns   5.358mV    36.67mV    3.074mV
20ns      2.128mV    1.725mV    2.736mV
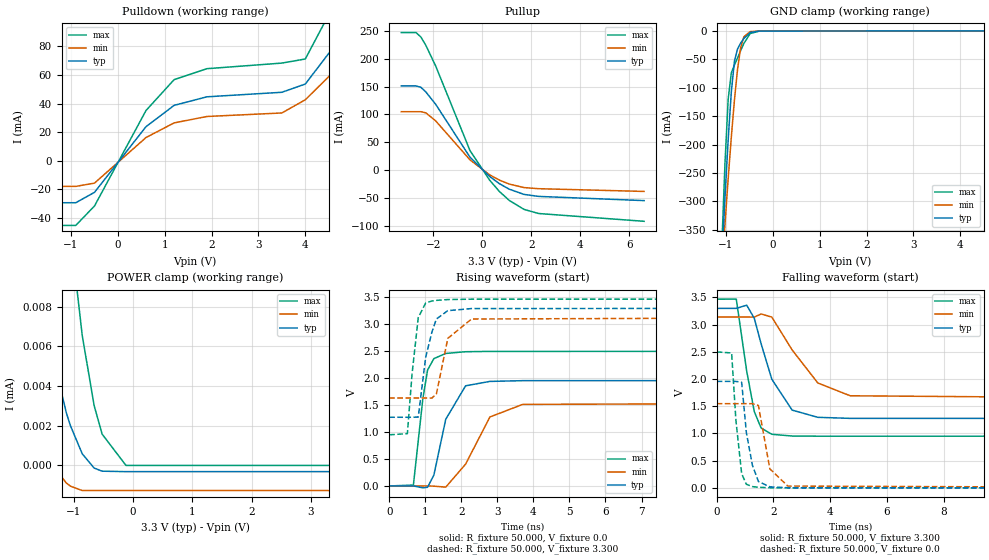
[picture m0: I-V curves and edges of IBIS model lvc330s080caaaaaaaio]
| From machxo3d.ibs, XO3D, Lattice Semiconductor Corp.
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|   Model lvc330s080caaaaaaaio
[Model] lvc330s080caaaaaaaio
Model_type I/O
Polarity   Non-Inverting
Enable   Active-Low
Vinl =  0.800V
Vinh =  2.000V
Vmeas =  1.650V
Cref =  0.0F
Rref =  1.000M
Vref =  0.0V
C_comp   4.200pF   3.800pF   7.500pF
[Temperature Range]   25.000   0.105k   -40.000
[Voltage Range]   3.300V   3.140V   3.470V
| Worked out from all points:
|   slope of the pulldown table from 0 to 0.495 V, typ, clamps not added: 24.3 ohm
|   slope of the pullup table from 0 to 0.495 V, typ, clamps not added: 26.7 ohm
|   GND clamp passes 1 mA (typ) near -0.43 V on its own axis
|   rising waveform, R_fixture 50.000, V_fixture 0.0: 20-80 % time 424ps typ, 676ps min, 237ps max; typ from 0 V to 1.96 V
|   rising waveform, R_fixture 50.000, V_fixture 3.300: 20-80 % time 304ps typ, 346ps min, 210ps max; typ from 1.27 V to 3.3 V
|   falling waveform, R_fixture 50.000, V_fixture 3.300: 20-80 % time 786ps typ, 1.19ns min, 448ps max; typ from 3.3 V to 1.27 V
|   falling waveform, R_fixture 50.000, V_fixture 0.0: 20-80 % time 314ps typ, 366ps min, 233ps max; typ from 1.96 V to 0 V
[Pulldown]
|Voltage   I(typ)   I(min)   I(max)
-3.3V     -29.32mA   -17.9mA    -45.21mA
-900mV    -29.32mA   -17.9mA    -45.21mA
-500mV    -22.04mA   -15.61mA   -31.59mA
600mV     23.9mA     16.31mA    35.23mA
1.2V      38.8mA     26.54mA    56.81mA
1.9V      44.78mA    31.02mA    64.46mA
3.5V      47.95mA    33.48mA    68.37mA
4V        53.73mA    42.73mA    71.25mA
4.7V      83.74mA    65.33mA    114.7mA
5.3V      118.2mA    90.4mA     168mA
5.9V      161.6mA    120.5mA    237.1mA
6.6V      222.1mA    159.6mA    335.7mA
[Pullup]
|Voltage   I(typ)   I(min)   I(max)
-3.3V     151.1mA    104.7mA    247mA
-2.7V     151.1mA    104.7mA    247mA
-2.5V     148.5mA    104.7mA    238.8mA
-2.3V     140.2mA    102.6mA    224mA
-1.9V     118mA      88.19mA    186.9mA
-500mV    22.88mA    18.06mA    34.67mA
300mV     -11.82mA   -8.831mA   -18.38mA
700mV     -24.77mA   -18.36mA   -38.83mA
1.1V      -34.65mA   -25.44mA   -54.83mA
1.7V      -44.02mA   -31.73mA   -70.96mA
2.3V      -47.65mA   -33.78mA   -78.43mA
6.6V      -55.19mA   -38.7mA    -92.41mA
[GND_clamp]
|Voltage   I(typ)   I(min)   I(max)
-3.3V     -4.507A    -3.482A    -6.263A
-1.089V   -398.4mA   -420.6mA   -374.7mA
-1.022V   -290.7mA   -338.6mA   -230.6mA
-955mV    -191.4mA   -260.2mA   -120.1mA
-888mV    -107.5mA   -187mA     -73.7mA
-821mV    -53mA      -121.4mA   -59.85mA
-754mV    -31.41mA   -66.94mA   -47.47mA
-687mV    -21.17mA   -28.82mA   -34.25mA
-620mV    -13.21mA   -10.23mA   -22mA
-486mV    -2.63mA    -1.112mA   -4.479mA
-285mV    -80.91uA   -42.41uA   -152.3uA
6.6V      121.2uA    55.82uA    291.2uA
[POWER_clamp]
|Voltage   I(typ)   I(min)   I(max)
-3.3V     704.7uA    440.9uA    1.167mA
-2.596V   46.79uA    12.42uA    184.2uA
-2.328V   25.67uA    8.107uA    76.87uA
-1.792V   13.09uA    2.762uA    43.68uA
-1.39V    5.98uA     124.1nA    24.26uA
-1.122V   2.656uA    -886.1nA   13.98uA
-1.055V   2.02uA     -1.042uA   11.85uA
-854mV    585.6nA    -1.267uA   6.557uA
-653mV    -133.8nA   -1.267uA   3.017uA
-519mV    -290.6nA   -1.267uA   1.58uA
-117mV    -313.6nA   -1.267uA   0A
3.3V      -313.6nA   -1.267uA   0A
[Ramp]
| variable   typ   min   max
dV/dt_r   1.174/0.424n   0.928/0.671n   1.499/0.236n
dV/dt_f   1.214/0.783n   0.904/1.195n   1.511/0.450n
R_load = 50.000
[Rising Waveform]
R_fixture= 50.000
V_fixture= 0.0
V_fixture_min= 0.0
V_fixture_max= 0.0
|time   V(typ)   V(min)   V(max)
0s        17.57nV    44.81nV    205.1nV
671ps     366.3uV    -3.257uV   16.47mV
934ps     -35.26mV   21.41uV    1.623V
1.064ns   -24.1mV    416.5uV    2.15V
1.239ns   201.6mV    -3.743mV   2.363V
1.569ns   1.238V     -21.73mV   2.459V
2.119ns   1.858V     404.8mV    2.491V
2.794ns   1.94V      1.28V      2.497V
3.704ns   1.954V     1.514V     2.497V
20ns      1.956V     1.547V     2.498V
[Rising Waveform]
R_fixture= 50.000
V_fixture= 3.300
V_fixture_min= 3.140
V_fixture_max= 3.470
|time   V(typ)   V(min)   V(max)
0s        1.275V     1.632V     949.1mV
504ps     1.275V     1.632V     971.3mV
634ps     1.275V     1.632V     2.078V
806ps     1.278V     1.632V     3.125V
1.012ns   2.388V     1.632V     3.395V
1.183ns   2.851V     1.63V      3.432V
1.309ns   3.099V     1.707V     3.444V
1.626ns   3.253V     2.739V     3.459V
2.284ns   3.292V     3.098V     3.466V
20ns      3.298V     3.139V     3.467V
[Falling Waveform]
R_fixture= 50.000
V_fixture= 3.300
V_fixture_min= 3.140
V_fixture_max= 3.470
|time   V(typ)   V(min)   V(max)
0s        3.298V     3.139V     3.467V
690ps     3.298V     3.139V     3.468V
1.056ns   3.357V     3.139V     2.147V
1.323ns   3.117V     3.138V     1.403V
1.565ns   2.646V     3.195V     1.099V
1.941ns   1.997V     3.138V     984.8mV
2.656ns   1.429V     2.535V     952.5mV
3.562ns   1.296V     1.927V     949.4mV
4.703ns   1.277V     1.692V     949.1mV
20ns      1.275V     1.632V     949mV
[Falling Waveform]
R_fixture= 50.000
V_fixture= 0.0
V_fixture_min= 0.0
V_fixture_max= 0.0
|time   V(typ)   V(min)   V(max)
0s        1.956V     1.547V     2.498V
526ps     1.956V     1.547V     2.479V
676ps     1.956V     1.547V     1.245V
879ps     1.939V     1.547V     260.5mV
1.045ns   1.015V     1.547V     65.88mV
1.257ns   417.6mV    1.547V     23.28mV
1.469ns   117.3mV    1.514V     10.46mV
1.872ns   18.89mV    349.7mV    2.209mV
2.504ns   3.093mV    32.55mV    309.6uV
20ns      72.47nV    114.4nV    217.9nV
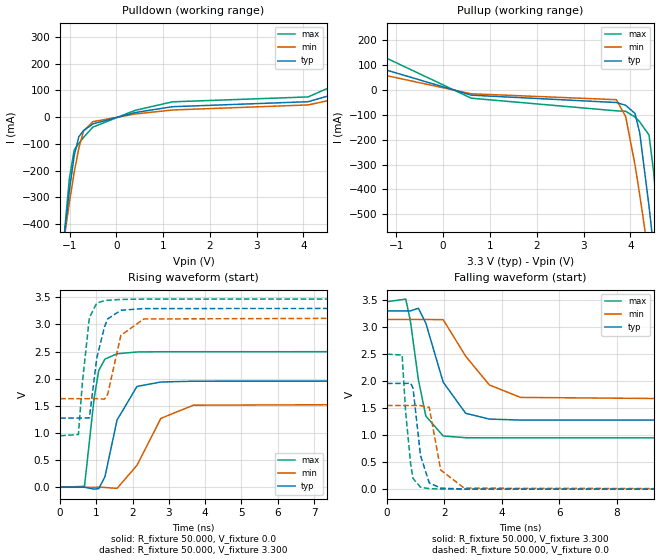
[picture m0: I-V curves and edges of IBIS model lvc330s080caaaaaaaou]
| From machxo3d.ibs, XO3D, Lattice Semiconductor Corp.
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|   Model lvc330s080caaaaaaaou
[Model] lvc330s080caaaaaaaou
Model_type Output
Polarity   Non-Inverting
Enable   Active-High
Vmeas =  1.650V
Cref =  0.0F
Rref =  1.000M
Vref =  0.0V
C_comp   4.200pF   3.800pF   7.500pF
[Temperature Range]   25.000   0.105k   -40.000
[Voltage Range]   3.300V   3.140V   3.470V
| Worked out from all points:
|   slope of the pulldown table from 0 to 0.495 V, typ, clamps not added: 24.2 ohm
|   slope of the pullup table from 0 to 0.495 V, typ, clamps not added: 26.7 ohm
|   rising waveform, R_fixture 50.000, V_fixture 0.0: 20-80 % time 424ps typ, 673ps min, 237ps max; typ from 0 V to 1.96 V
|   rising waveform, R_fixture 50.000, V_fixture 3.300: 20-80 % time 302ps typ, 348ps min, 210ps max; typ from 1.27 V to 3.3 V
|   falling waveform, R_fixture 50.000, V_fixture 3.300: 20-80 % time 780ps typ, 1.19ns min, 450ps max; typ from 3.3 V to 1.27 V
|   falling waveform, R_fixture 50.000, V_fixture 0.0: 20-80 % time 313ps typ, 366ps min, 233ps max; typ from 1.96 V to 0 V
[Pulldown]
|Voltage   I(typ)   I(min)   I(max)
-3.3V     -4.507A    -3.482A    -6.263A
-1.1V     -423.4mA   -437.5mA   -416.7mA
-1V       -269.7mA   -316.9mA   -225.2mA
-900mV    -144.5mA   -206.8mA   -123.1mA
-800mV    -72.92mA   -115.2mA   -98.44mA
-700mV    -50.73mA   -52.05mA   -75.91mA
-500mV    -25.36mA   -17.06mA   -37.28mA
400mV     17mA       11.58mA    25.12mA
1.2V      38.9mA     26.58mA    57.05mA
4.1V      57.52mA    45.55mA    75.45mA
5.3V      118.3mA    90.45mA    168.3mA
6.6V      222.9mA    160.3mA    336.9mA
[Pullup]
|Voltage   I(typ)   I(min)   I(max)
-3.3V     151.3mA    104.8mA    247.6mA
-2.4V     144.9mA    104.6mA    232.3mA
600mV     -21.72mA   -16.17mA   -33.89mA
3.7V      -51.21mA   -39.84mA   -84.53mA
3.9V      -62.28mA   -107.4mA   -86.46mA
4.1V      -95.15mA   -302.3mA   -109.5mA
4.2V      -172.6mA   -421.2mA   -128.8mA
4.4V      -468.8mA   -676.6mA   -181.9mA
4.5V      -639.3mA   -809mA     -333.7mA
4.6V      -815.4mA   -943.4mA   -557.7mA
4.7V      -994.9mA   -1.079A    -803mA
6.6V      -4.562A    -3.748A    -5.893A
[Ramp]
| variable   typ   min   max
dV/dt_r   1.174/0.424n   0.928/0.671n   1.499/0.236n
dV/dt_f   1.214/0.783n   0.904/1.195n   1.511/0.450n
R_load = 50.000
[Rising Waveform]
R_fixture= 50.000
V_fixture= 0.0
V_fixture_min= 0.0
V_fixture_max= 0.0
|time   V(typ)   V(min)   V(max)
0s        17.57nV    44.81nV    205.1nV
671ps     352.7uV    -5.182uV   16.48mV
935ps     -35.25mV   93.04uV    1.629V
1.064ns   -24.1mV    403.6uV    2.15V
1.235ns   191.5mV    -3.612mV   2.361V
1.569ns   1.238V     -21.61mV   2.459V
2.119ns   1.857V     404.8mV    2.492V
2.778ns   1.939V     1.269V     2.497V
3.678ns   1.954V     1.512V     2.497V
20ns      1.956V     1.547V     2.498V
[Rising Waveform]
R_fixture= 50.000
V_fixture= 3.300
V_fixture_min= 3.140
V_fixture_max= 3.470
|time   V(typ)   V(min)   V(max)
0s        1.275V     1.632V     949.1mV
504ps     1.275V     1.632V     971.3mV
610ps     1.275V     1.632V     1.906V
806ps     1.278V     1.632V     3.125V
1.01ns    2.38V      1.632V     3.394V
1.223ns   2.954V     1.623V     3.437V
1.311ns   3.102V     1.712V     3.445V
1.674ns   3.26V      2.798V     3.46V
2.304ns   3.292V     3.1V       3.466V
20ns      3.298V     3.139V     3.467V
[Falling Waveform]
R_fixture= 50.000
V_fixture= 3.300
V_fixture_min= 3.140
V_fixture_max= 3.470
|time   V(typ)   V(min)   V(max)
0s        3.298V     3.139V     3.467V
652ps     3.298V     3.139V     3.516V
812ps     3.296V     3.139V     3.115V
1.089ns   3.346V     3.139V     2.032V
1.35ns    3.071V     3.138V     1.353V
1.954ns   1.979V     3.135V     983.5mV
2.737ns   1.403V     2.459V     951.7mV
3.562ns   1.296V     1.927V     949.4mV
4.641ns   1.278V     1.697V     949mV
20ns      1.275V     1.632V     949mV
[Falling Waveform]
R_fixture= 50.000
V_fixture= 0.0
V_fixture_min= 0.0
V_fixture_max= 0.0
|time   V(typ)   V(min)   V(max)
0s        1.956V     1.547V     2.498V
526ps     1.956V     1.547V     2.479V
646ps     1.956V     1.547V     1.436V
827ps     1.959V     1.547V     444.8mV
905ps     1.867V     1.547V     199.9mV
1.165ns   622.7mV    1.546V     35.12mV
1.469ns   116.6mV    1.514V     10.37mV
1.868ns   19.4mV     354.2mV    2.525mV
2.687ns   1.914mV    18.92mV    213.1uV
20ns      72.01nV    210.8nV    225.8nV
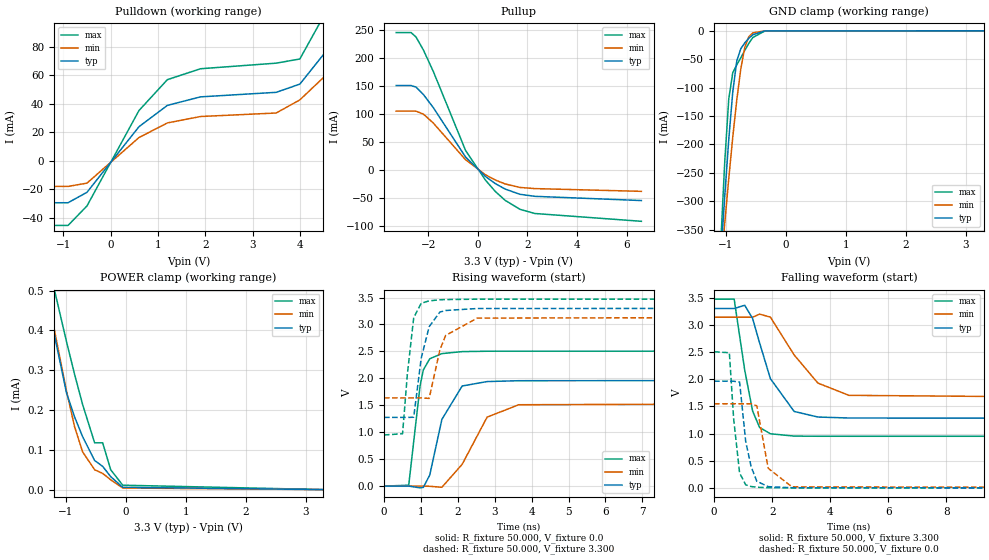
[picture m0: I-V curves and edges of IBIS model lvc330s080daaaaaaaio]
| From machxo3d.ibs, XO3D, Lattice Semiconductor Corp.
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|   Model lvc330s080daaaaaaaio
[Model] lvc330s080daaaaaaaio
Model_type I/O
Polarity   Non-Inverting
Enable   Active-Low
Vinl =  0.800V
Vinh =  2.000V
Vmeas =  1.650V
Cref =  0.0F
Rref =  1.000M
Vref =  0.0V
C_comp   4.200pF   3.800pF   7.500pF
[Temperature Range]   25.000   0.105k   -40.000
[Voltage Range]   3.300V   3.140V   3.470V
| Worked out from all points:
|   slope of the pulldown table from 0 to 0.495 V, typ, clamps not added: 24.3 ohm
|   slope of the pullup table from 0 to 0.495 V, typ, clamps not added: 26.7 ohm
|   GND clamp passes 1 mA (typ) near -0.43 V on its own axis
|   POWER clamp passes 1 mA (typ) near -1.85 V on its own axis
|   rising waveform, R_fixture 50.000, V_fixture 0.0: 20-80 % time 427ps typ, 676ps min, 237ps max; typ from 0 V to 1.96 V
|   rising waveform, R_fixture 50.000, V_fixture 3.300: 20-80 % time 304ps typ, 347ps min, 210ps max; typ from 1.27 V to 3.3 V
|   falling waveform, R_fixture 50.000, V_fixture 3.300: 20-80 % time 797ps typ, 1.2ns min, 455ps max; typ from 3.3 V to 1.27 V
|   falling waveform, R_fixture 50.000, V_fixture 0.0: 20-80 % time 318ps typ, 366ps min, 236ps max; typ from 1.96 V to 0 V
[Pulldown]
|Voltage   I(typ)   I(min)   I(max)
-3.3V     -29.32mA   -17.9mA    -45.21mA
-900mV    -29.32mA   -17.9mA    -45.21mA
-500mV    -22.04mA   -15.61mA   -31.59mA
600mV     23.9mA     16.31mA    35.23mA
1.2V      38.8mA     26.54mA    56.81mA
1.9V      44.78mA    31.02mA    64.46mA
3.5V      47.95mA    33.48mA    68.37mA
4V        53.7mA     42.66mA    71.29mA
4.6V      78.57mA    61.48mA    107.1mA
5.3V      117.8mA    90.43mA    167.3mA
5.9V      161.4mA    121.1mA    236.3mA
6.6V      221.9mA    162.1mA    331.9mA
[Pullup]
|Voltage   I(typ)   I(min)   I(max)
-3.3V     151mA      105.1mA    246mA
-2.7V     151mA      105.1mA    246mA
-2.5V     148.2mA    105.1mA    238mA
-2.2V     134.8mA    99.77mA    214.6mA
-1.8V     111.3mA    83.67mA    176.1mA
-500mV    22.89mA    18.05mA    34.72mA
300mV     -11.82mA   -8.831mA   -18.38mA
700mV     -24.77mA   -18.36mA   -38.83mA
1.1V      -34.65mA   -25.44mA   -54.83mA
1.7V      -44.02mA   -31.73mA   -70.96mA
2.3V      -47.65mA   -33.78mA   -78.43mA
6.6V      -55.19mA   -38.7mA    -92.41mA
[GND_clamp]
|Voltage   I(typ)   I(min)   I(max)
-3.3V     -4.507A    -3.482A    -6.263A
-1.089V   -398.4mA   -420.6mA   -374.7mA
-1.022V   -290.7mA   -338.6mA   -230.6mA
-955mV    -191.4mA   -260.2mA   -120.1mA
-888mV    -107.5mA   -187mA     -73.7mA
-821mV    -53mA      -121.4mA   -59.85mA
-754mV    -31.41mA   -66.94mA   -47.47mA
-687mV    -21.17mA   -28.82mA   -34.25mA
-620mV    -13.21mA   -10.23mA   -22mA
-553mV    -6.875mA   -3.578mA   -11.73mA
-352mV    -176.3uA   -89.98uA   -279uA
3.3V      50.87nA    0A         -26.43uA
[POWER_clamp]
|Voltage   I(typ)   I(min)   I(max)
-3.3V     3.967mA    2.512mA    11.53mA
-1.323V   507.3uA    506.4uA    605.6uA
-1.256V   446.6uA    452.8uA    548.7uA
-1.189V   387.7uA    399.8uA    501.1uA
-988mV    242.5uA    247.5uA    371.4uA
-854mV    182.6uA    158.2uA    289.7uA
-720mV    133.1uA    94.82uA    213.9uA
-519mV    73.06uA    49.89uA    117.5uA
-385mV    58.36uA    40.66uA    117.5uA
-251mV    32.53uA    24.74uA    49.87uA
-50mV     5.761uA    3.987uA    11.09uA
3.3V      0A         0A         0A
[Ramp]
| variable   typ   min   max
dV/dt_r   1.177/0.427n   0.928/0.671n   1.503/0.237n
dV/dt_f   1.215/0.791n   0.902/1.193n   1.513/0.456n
R_load = 50.000
[Rising Waveform]
R_fixture= 50.000
V_fixture= 0.0
V_fixture_min= 0.0
V_fixture_max= 0.0
|time   V(typ)   V(min)   V(max)
0s        17.57nV    44.81nV    205.1nV
671ps     366.3uV    -3.276uV   16.47mV
978ps     -32.61mV   21.41uV    1.859V
1.066ns   -23.69mV   416.5uV    2.155V
1.24ns    204.1mV    -3.743mV   2.363V
1.569ns   1.238V     -21.73mV   2.459V
2.119ns   1.858V     404.8mV    2.496V
2.794ns   1.94V      1.28V      2.503V
3.652ns   1.956V     1.51V      2.504V
20ns      1.962V     1.547V     2.504V
[Rising Waveform]
R_fixture= 50.000
V_fixture= 3.300
V_fixture_min= 3.140
V_fixture_max= 3.470
|time   V(typ)   V(min)   V(max)
0s        1.275V     1.637V     949.1mV
504ps     1.275V     1.637V     971.3mV
634ps     1.275V     1.637V     2.078V
806ps     1.278V     1.637V     3.125V
1.008ns   2.371V     1.637V     3.393V
1.225ns   2.958V     1.628V     3.438V
1.513ns   3.229V     2.523V     3.458V
1.669ns   3.259V     2.795V     3.462V
2.528ns   3.296V     3.118V     3.469V
20ns      3.3V       3.14V      3.47V
[Falling Waveform]
R_fixture= 50.000
V_fixture= 3.300
V_fixture_min= 3.140
V_fixture_max= 3.470
|time   V(typ)   V(min)   V(max)
0s        3.3V       3.14V      3.47V
692ps     3.299V     3.14V      3.472V
1.055ns   3.359V     3.14V      2.165V
1.328ns   3.114V     3.139V     1.411V
1.568ns   2.665V     3.196V     1.111V
1.938ns   2.01V      3.141V     995.3mV
2.756ns   1.406V     2.446V     952.3mV
3.572ns   1.303V     1.928V     949.4mV
4.642ns   1.285V     1.702V     949.1mV
20ns      1.275V     1.637V     949mV
[Falling Waveform]
R_fixture= 50.000
V_fixture= 0.0
V_fixture_min= 0.0
V_fixture_max= 0.0
|time   V(typ)   V(min)   V(max)
0s        1.962V     1.547V     2.504V
526ps     1.962V     1.547V     2.486V
674ps     1.962V     1.547V     1.272V
879ps     1.945V     1.547V     273.9mV
1.089ns   850.9mV    1.547V     56.2mV
1.277ns   387.7mV    1.547V     24.58mV
1.471ns   122mV      1.51V      11.7mV
1.863ns   22.37mV    360.2mV    2.732mV
2.679ns   2.642mV    18.91mV    249.5uV
20ns      69.04nV    114.4nV    213.2nV
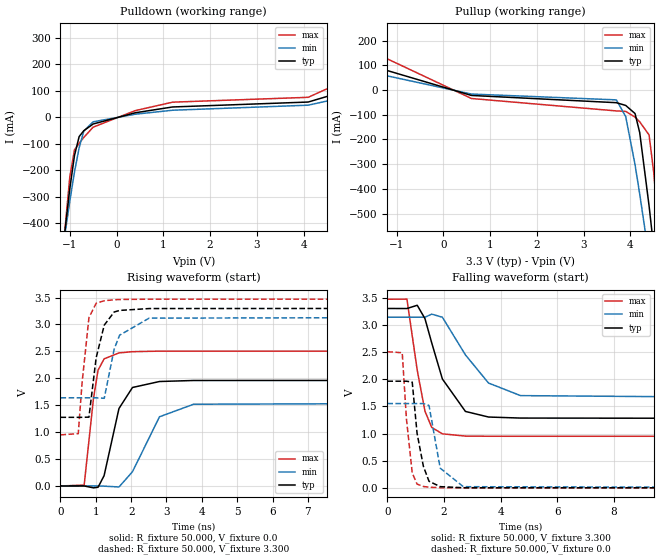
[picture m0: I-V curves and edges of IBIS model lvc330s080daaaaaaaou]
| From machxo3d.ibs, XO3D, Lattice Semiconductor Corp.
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|   Model lvc330s080daaaaaaaou
[Model] lvc330s080daaaaaaaou
Model_type Output
Polarity   Non-Inverting
Enable   Active-High
Vmeas =  1.650V
Cref =  0.0F
Rref =  1.000M
Vref =  0.0V
C_comp   4.200pF   3.800pF   7.500pF
[Temperature Range]   25.000   0.105k   -40.000
[Voltage Range]   3.300V   3.140V   3.470V
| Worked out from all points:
|   slope of the pulldown table from 0 to 0.495 V, typ, clamps not added: 24.2 ohm
|   slope of the pullup table from 0 to 0.495 V, typ, clamps not added: 26.6 ohm
|   rising waveform, R_fixture 50.000, V_fixture 0.0: 20-80 % time 427ps typ, 680ps min, 238ps max; typ from 0 V to 1.96 V
|   rising waveform, R_fixture 50.000, V_fixture 3.300: 20-80 % time 302ps typ, 347ps min, 210ps max; typ from 1.27 V to 3.3 V
|   falling waveform, R_fixture 50.000, V_fixture 3.300: 20-80 % time 793ps typ, 1.2ns min, 455ps max; typ from 3.3 V to 1.27 V
|   falling waveform, R_fixture 50.000, V_fixture 0.0: 20-80 % time 318ps typ, 371ps min, 236ps max; typ from 1.96 V to 0 V
[Pulldown]
|Voltage   I(typ)   I(min)   I(max)
-3.3V     -4.507A    -3.482A    -6.263A
-1.1V     -423.4mA   -437.5mA   -416.7mA
-1V       -269.7mA   -316.9mA   -225.2mA
-900mV    -144.5mA   -206.8mA   -123.1mA
-800mV    -72.92mA   -115.2mA   -98.44mA
-700mV    -50.73mA   -52.05mA   -75.91mA
-500mV    -25.36mA   -17.06mA   -37.28mA
400mV     17mA       11.58mA    25.12mA
1.2V      38.9mA     26.58mA    57.05mA
4.1V      57.51mA    45.64mA    75.36mA
5.4V      125.6mA    96.49mA    179mA
6.6V      225.7mA    164.9mA    339mA
[Pullup]
|Voltage   I(typ)   I(min)   I(max)
-3.3V     152.9mA    106.6mA    248.9mA
-2.4V     145.9mA    106.3mA    233.1mA
600mV     -21.89mA   -16.25mA   -34.23mA
3.7V      -51.21mA   -39.84mA   -84.53mA
3.9V      -62.28mA   -107.4mA   -86.46mA
4.1V      -95.15mA   -302.3mA   -109.5mA
4.2V      -172.6mA   -421.2mA   -128.8mA
4.4V      -468.8mA   -676.6mA   -181.9mA
4.5V      -639.3mA   -809mA     -333.7mA
4.6V      -815.4mA   -943.4mA   -557.7mA
4.7V      -994.9mA   -1.079A    -803mA
6.6V      -4.562A    -3.748A    -5.893A
[Ramp]
| variable   typ   min   max
dV/dt_r   1.177/0.427n   0.931/0.675n   1.503/0.237n
dV/dt_f   1.215/0.791n   0.902/1.193n   1.513/0.456n
R_load = 50.000
[Rising Waveform]
R_fixture= 50.000
V_fixture= 0.0
V_fixture_min= 0.0
V_fixture_max= 0.0
|time   V(typ)   V(min)   V(max)
0s        17.57nV    44.81nV    205.1nV
671ps     352.6uV    -5.201uV   16.48mV
935ps     -35.25mV   93.04uV    1.629V
1.064ns   -24.1mV    403.6uV    2.15V
1.235ns   191.5mV    -3.612mV   2.361V
1.656ns   1.439V     -18.68mV   2.471V
2.038ns   1.829V     264.3mV    2.494V
2.802ns   1.94V      1.285V     2.504V
3.769ns   1.959V     1.518V     2.504V
20ns      1.962V     1.551V     2.504V
[Rising Waveform]
R_fixture= 50.000
V_fixture= 3.300
V_fixture_min= 3.140
V_fixture_max= 3.470
|time   V(typ)   V(min)   V(max)
0s        1.275V     1.637V     949.1mV
504ps     1.275V     1.637V     971.3mV
610ps     1.275V     1.637V     1.906V
806ps     1.278V     1.637V     3.125V
1.01ns    2.38V      1.637V     3.394V
1.239ns   2.987V     1.628V     3.44V
1.52ns    3.231V     2.541V     3.458V
1.673ns   3.26V      2.8V       3.463V
2.51ns    3.295V     3.117V     3.469V
20ns      3.3V       3.14V      3.47V
[Falling Waveform]
R_fixture= 50.000
V_fixture= 3.300
V_fixture_min= 3.140
V_fixture_max= 3.470
|time   V(typ)   V(min)   V(max)
0s        3.3V       3.14V      3.47V
692ps     3.299V     3.14V      3.472V
1.055ns   3.359V     3.14V      2.165V
1.328ns   3.114V     3.139V     1.411V
1.568ns   2.665V     3.196V     1.111V
1.943ns   2.003V     3.139V     994.1mV
2.756ns   1.406V     2.446V     952.3mV
3.572ns   1.303V     1.928V     949.4mV
4.701ns   1.284V     1.697V     949mV
20ns      1.275V     1.637V     949mV
[Falling Waveform]
R_fixture= 50.000
V_fixture= 0.0
V_fixture_min= 0.0
V_fixture_max= 0.0
|time   V(typ)   V(min)   V(max)
0s        1.962V     1.551V     2.504V
526ps     1.962V     1.551V     2.486V
674ps     1.962V     1.551V     1.272V
879ps     1.945V     1.551V     273.9mV
1.05ns    1.002V     1.551V     69.17mV
1.273ns   395.7mV    1.551V     25.49mV
1.471ns   121.4mV    1.515V     12.04mV
1.866ns   22.44mV    362.7mV    2.658mV
2.684ns   2.692mV    21.55mV    235.5uV
20ns      65.66nV    208.4nV    218.7nV
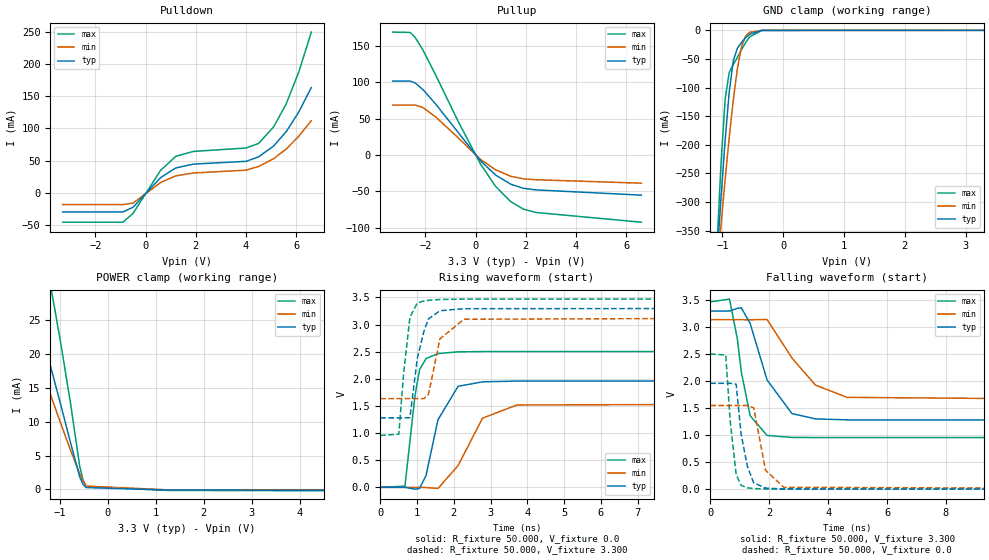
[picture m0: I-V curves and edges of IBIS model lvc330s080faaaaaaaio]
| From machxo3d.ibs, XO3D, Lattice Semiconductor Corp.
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|   Model lvc330s080faaaaaaaio
[Model] lvc330s080faaaaaaaio
Model_type I/O
Polarity   Non-Inverting
Enable   Active-Low
Vinl =  0.800V
Vinh =  2.000V
Vmeas =  1.650V
Cref =  0.0F
Rref =  1.000M
Vref =  0.0V
C_comp   4.200pF   3.800pF   7.500pF
[Temperature Range]   25.000   0.105k   -40.000
[Voltage Range]   3.300V   3.140V   3.470V
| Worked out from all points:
|   slope of the pulldown table from 0 to 0.495 V, typ, clamps not added: 24.3 ohm
|   slope of the pullup table from 0 to 0.495 V, typ, clamps not added: 26.7 ohm
|   GND clamp passes 1 mA (typ) near -0.43 V on its own axis
|   POWER clamp passes 1 mA (typ) near -0.53 V on its own axis
|   rising waveform, R_fixture 50.000, V_fixture 0.0: 20-80 % time 423ps typ, 672ps min, 236ps max; typ from 0.002 V to 1.96 V
|   rising waveform, R_fixture 50.000, V_fixture 3.300: 20-80 % time 300ps typ, 346ps min, 209ps max; typ from 1.28 V to 3.3 V
|   falling waveform, R_fixture 50.000, V_fixture 3.300: 20-80 % time 784ps typ, 1.19ns min, 453ps max; typ from 3.3 V to 1.28 V
|   falling waveform, R_fixture 50.000, V_fixture 0.0: 20-80 % time 317ps typ, 369ps min, 236ps max; typ from 1.96 V to 0.002 V
[Pulldown]
|Voltage   I(typ)   I(min)   I(max)
-3.3V     -29.32mA   -17.9mA    -45.21mA
-900mV    -29.32mA   -17.9mA    -45.21mA
-500mV    -22.04mA   -15.61mA   -31.59mA
600mV     23.9mA     16.31mA    35.23mA
1.2V      38.8mA     26.54mA    56.81mA
1.9V      44.78mA    31.02mA    64.46mA
4V        49.1mA     35.45mA    69.72mA
4.5V      56.03mA    41.14mA    76.83mA
5.1V      72.88mA    53.19mA    102.5mA
5.6V      95.13mA    68.16mA    138.2mA
6.1V      125.5mA    87.96mA    187.4mA
6.6V      163.5mA    112.1mA    249.4mA
[Pullup]
|Voltage   I(typ)   I(min)   I(max)
-3.3V     101.8mA    68.84mA    169.3mA
-2.6V     101.8mA    68.84mA    168.8mA
-2.4V     99.18mA    68.84mA    161.7mA
-2.1V     90.23mA    65.49mA    144.8mA
-1.6V     70.72mA    52.87mA    111mA
-700mV    31.42mA    23.96mA    46.76mA
200mV     -8.086mA   -6.051mA   -12.55mA
800mV     -27.53mA   -20.35mA   -43.24mA
1.4V      -40.13mA   -29.21mA   -64.05mA
1.9V      -45.78mA   -32.75mA   -74.34mA
2.4V      -47.94mA   -33.97mA   -79.05mA
6.6V      -55.19mA   -38.7mA    -92.41mA
[GND_clamp]
|Voltage   I(typ)   I(min)   I(max)
-3.3V     -4.506A    -3.482A    -6.262A
-1.089V   -398.3mA   -420.5mA   -374.5mA
-1.022V   -290.6mA   -338.5mA   -230.4mA
-955mV    -191.2mA   -260.1mA   -119.8mA
-888mV    -107.4mA   -186.9mA   -73.47mA
-821mV    -52.87mA   -121.3mA   -59.62mA
-754mV    -31.28mA   -66.86mA   -47.24mA
-687mV    -21.04mA   -28.74mA   -34.02mA
-620mV    -13.09mA   -10.15mA   -21.79mA
-553mV    -6.755mA   -3.505mA   -11.52mA
-352mV    -90.18uA   -45.39uA   -119.9uA
3.3V      0A         0A         0A
[POWER_clamp]
|Voltage   I(typ)   I(min)   I(max)
-3.3V     62.1mA     51.02mA    92.7mA
-1.926V   36.35mA    28.59mA    56.55mA
-1.591V   28.28mA    21.98mA    45.01mA
-1.189V   18.03mA    13.9mA     29.96mA
-1.122V   16.26mA    12.55mA    27.31mA
-988mV    12.68mA    9.882mA    21.88mA
-787mV    7.154mA    5.963mA    13.15mA
-586mV    1.819mA    2.29mA     3.395mA
-519mV    748.7uA    1.242mA    1.434mA
-452mV    255.4uA    468.1uA    442.9uA
1.223V    -104.1uA   -69.89uA   -164.8uA
6.6V      -145.9uA   -91.75uA   -251.2uA
[Ramp]
| variable   typ   min   max
dV/dt_r   1.176/0.423n   0.930/0.671n   1.501/0.235n
dV/dt_f   1.211/0.786n   0.902/1.193n   1.507/0.453n
R_load = 50.000
[Rising Waveform]
R_fixture= 50.000
V_fixture= 0.0
V_fixture_min= 0.0
V_fixture_max= 0.0
|time   V(typ)   V(min)   V(max)
0s        2.128mV    1.725mV    2.736mV
671ps     2.486mV    1.72mV     23.2mV
942ps     -31.71mV   1.797mV    1.683V
1.067ns   -18.81mV   2.129mV    2.167V
1.243ns   217.7mV    -2.538mV   2.373V
1.57ns    1.249V     -18.7mV    2.466V
2.115ns   1.863V     402.4mV    2.498V
2.78ns    1.945V     1.276V     2.503V
3.718ns   1.96V      1.519V     2.504V
20ns      1.962V     1.551V     2.504V
[Rising Waveform]
R_fixture= 50.000
V_fixture= 3.300
V_fixture_min= 3.140
V_fixture_max= 3.470
|time   V(typ)   V(min)   V(max)
0s        1.282V     1.637V     957.6mV
504ps     1.282V     1.637V     980.8mV
635ps     1.282V     1.637V     2.101V
806ps     1.285V     1.637V     3.134V
1.007ns   2.376V     1.637V     3.397V
1.183ns   2.868V     1.634V     3.435V
1.31ns    3.105V     1.714V     3.447V
1.624ns   3.255V     2.739V     3.462V
2.28ns    3.293V     3.098V     3.469V
20ns      3.3V       3.14V      3.47V
[Falling Waveform]
R_fixture= 50.000
V_fixture= 3.300
V_fixture_min= 3.140
V_fixture_max= 3.470
|time   V(typ)   V(min)   V(max)
0s        3.3V       3.14V      3.47V
653ps     3.3V       3.14V      3.522V
922ps     3.351V     3.14V      2.776V
1.055ns   3.359V     3.14V      2.165V
1.355ns   3.068V     3.138V     1.361V
1.928ns   2.024V     3.144V     996.5mV
2.774ns   1.401V     2.43V      960mV
3.572ns   1.303V     1.928V     957.9mV
4.642ns   1.285V     1.702V     957.6mV
20ns      1.282V     1.637V     957.6mV
[Falling Waveform]
R_fixture= 50.000
V_fixture= 0.0
V_fixture_min= 0.0
V_fixture_max= 0.0
|time   V(typ)   V(min)   V(max)
0s        1.962V     1.551V     2.504V
526ps     1.962V     1.551V     2.486V
674ps     1.962V     1.551V     1.272V
879ps     1.945V     1.551V     273.9mV
1.045ns   1.024V     1.551V     71.83mV
1.261ns   420.3mV    1.551V     26.5mV
1.474ns   119.9mV    1.509V     12.92mV
1.878ns   21.27mV    349.2mV    5.185mV
2.498ns   5.348mV    36.16mV    3.123mV
20ns      2.128mV    1.725mV    2.736mV
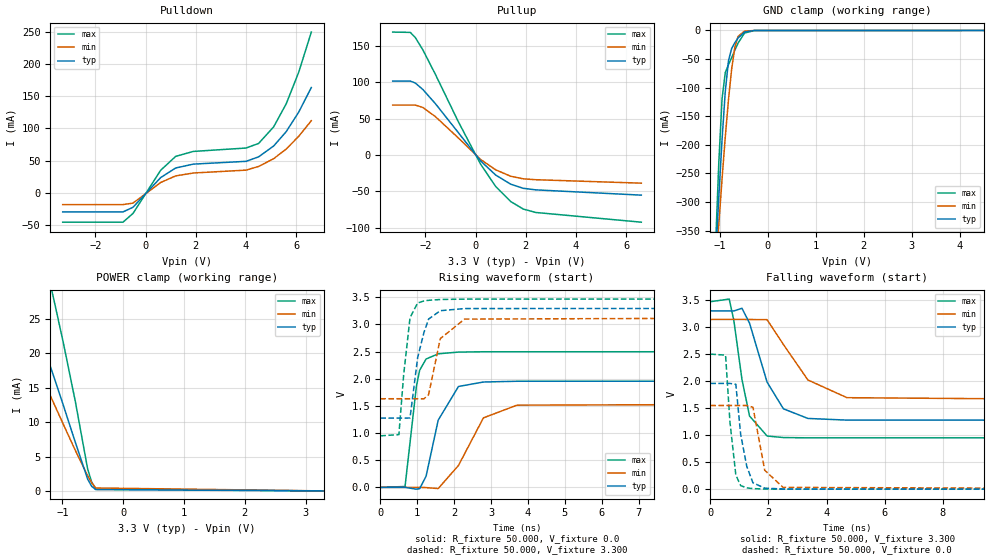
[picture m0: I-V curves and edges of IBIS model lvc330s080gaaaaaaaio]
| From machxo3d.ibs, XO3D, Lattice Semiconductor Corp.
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|   Model lvc330s080gaaaaaaaio
[Model] lvc330s080gaaaaaaaio
Model_type I/O
Polarity   Non-Inverting
Enable   Active-Low
Vinl =  0.800V
Vinh =  2.000V
Vmeas =  1.650V
Cref =  0.0F
Rref =  1.000M
Vref =  0.0V
C_comp   4.200pF   3.800pF   7.500pF
[Temperature Range]   25.000   0.105k   -40.000
[Voltage Range]   3.300V   3.140V   3.470V
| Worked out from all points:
|   slope of the pulldown table from 0 to 0.495 V, typ, clamps not added: 24.3 ohm
|   slope of the pullup table from 0 to 0.495 V, typ, clamps not added: 26.7 ohm
|   GND clamp passes 1 mA (typ) near -0.43 V on its own axis
|   POWER clamp passes 1 mA (typ) near -0.54 V on its own axis
|   rising waveform, R_fixture 50.000, V_fixture 0.0: 20-80 % time 424ps typ, 676ps min, 236ps max; typ from 0 V to 1.96 V
|   rising waveform, R_fixture 50.000, V_fixture 3.300: 20-80 % time 302ps typ, 346ps min, 210ps max; typ from 1.27 V to 3.3 V
|   falling waveform, R_fixture 50.000, V_fixture 3.300: 20-80 % time 780ps typ, 1.19ns min, 450ps max; typ from 3.3 V to 1.27 V
|   falling waveform, R_fixture 50.000, V_fixture 0.0: 20-80 % time 314ps typ, 366ps min, 233ps max; typ from 1.96 V to 0 V
[Pulldown]
|Voltage   I(typ)   I(min)   I(max)
-3.3V     -29.32mA   -17.9mA    -45.21mA
-900mV    -29.32mA   -17.9mA    -45.21mA
-500mV    -22.04mA   -15.61mA   -31.59mA
600mV     23.9mA     16.31mA    35.23mA
1.2V      38.8mA     26.54mA    56.81mA
1.9V      44.78mA    31.02mA    64.46mA
4V        49.1mA     35.45mA    69.72mA
4.5V      56.03mA    41.14mA    76.83mA
5.1V      72.88mA    53.19mA    102.5mA
5.6V      95.14mA    68.16mA    138.2mA
6.1V      125.5mA    87.96mA    187.4mA
6.6V      163.5mA    112.1mA    249.4mA
[Pullup]
|Voltage   I(typ)   I(min)   I(max)
-3.3V     101.8mA    68.78mA    169.2mA
-2.6V     101.8mA    68.78mA    168.8mA
-2.4V     99.14mA    68.78mA    161.7mA
-2.1V     90.21mA    65.46mA    144.8mA
-1.6V     70.71mA    52.86mA    111mA
-700mV    31.42mA    23.96mA    46.76mA
200mV     -8.086mA   -6.051mA   -12.55mA
800mV     -27.53mA   -20.35mA   -43.24mA
1.4V      -40.13mA   -29.21mA   -64.05mA
1.9V      -45.78mA   -32.75mA   -74.34mA
2.4V      -47.94mA   -33.97mA   -79.05mA
6.6V      -55.19mA   -38.7mA    -92.41mA
[GND_clamp]
|Voltage   I(typ)   I(min)   I(max)
-3.3V     -4.507A    -3.482A    -6.263A
-1.089V   -398.4mA   -420.6mA   -374.7mA
-1.022V   -290.7mA   -338.6mA   -230.6mA
-955mV    -191.4mA   -260.2mA   -120.1mA
-888mV    -107.5mA   -187mA     -73.7mA
-821mV    -53mA      -121.4mA   -59.85mA
-754mV    -31.41mA   -66.94mA   -47.47mA
-687mV    -21.17mA   -28.82mA   -34.25mA
-620mV    -13.21mA   -10.23mA   -22mA
-486mV    -2.63mA    -1.112mA   -4.479mA
-285mV    -80.91uA   -42.41uA   -152.3uA
6.6V      121.2uA    55.84uA    291.2uA
[POWER_clamp]
|Voltage   I(typ)   I(min)   I(max)
-3.3V     59.17mA    46.96mA    89.71mA
-1.993V   37.21mA    28.87mA    58.18mA
-1.926V   35.73mA    27.67mA    56.02mA
-1.591V   27.93mA    21.43mA    44.63mA
-1.189V   17.84mA    13.65mA    29.69mA
-1.122V   16.09mA    12.35mA    27.06mA
-988mV    12.53mA    9.74mA     21.66mA
-787mV    7.047mA    5.88mA     12.98mA
-586mV    1.736mA    2.238mA    3.233mA
-519mV    672uA      1.196mA    1.278mA
-452mV    189uA      428.3uA    309.6uA
3.3V      0A         0A         0A
[Ramp]
| variable   typ   min   max
dV/dt_r   1.174/0.424n   0.928/0.671n   1.499/0.236n
dV/dt_f   1.214/0.783n   0.904/1.195n   1.511/0.450n
R_load = 50.000
[Rising Waveform]
R_fixture= 50.000
V_fixture= 0.0
V_fixture_min= 0.0
V_fixture_max= 0.0
|time   V(typ)   V(min)   V(max)
0s        17.57nV    44.81nV    205.1nV
671ps     366.3uV    -3.259uV   16.47mV
978ps     -32.61mV   21.4uV     1.859V
1.066ns   -23.69mV   416.5uV    2.155V
1.24ns    204.1mV    -3.743mV   2.363V
1.569ns   1.238V     -21.73mV   2.459V
2.119ns   1.858V     404.8mV    2.491V
2.794ns   1.94V      1.28V      2.497V
3.704ns   1.954V     1.514V     2.497V
20ns      1.956V     1.547V     2.498V
[Rising Waveform]
R_fixture= 50.000
V_fixture= 3.300
V_fixture_min= 3.140
V_fixture_max= 3.470
|time   V(typ)   V(min)   V(max)
0s        1.275V     1.632V     949.1mV
504ps     1.275V     1.632V     971.3mV
634ps     1.275V     1.632V     2.078V
806ps     1.278V     1.632V     3.125V
1.012ns   2.388V     1.632V     3.395V
1.183ns   2.851V     1.63V      3.432V
1.309ns   3.099V     1.707V     3.444V
1.626ns   3.253V     2.739V     3.459V
2.284ns   3.292V     3.098V     3.466V
20ns      3.298V     3.139V     3.467V
[Falling Waveform]
R_fixture= 50.000
V_fixture= 3.300
V_fixture_min= 3.140
V_fixture_max= 3.470
|time   V(typ)   V(min)   V(max)
0s        3.298V     3.139V     3.467V
652ps     3.298V     3.139V     3.516V
812ps     3.296V     3.139V     3.115V
1.089ns   3.346V     3.139V     2.032V
1.35ns    3.071V     3.138V     1.353V
1.954ns   1.979V     3.135V     983.5mV
2.516ns   1.486V     2.675V     954.4mV
3.359ns   1.308V     2.019V     949.5mV
4.703ns   1.277V     1.692V     949.1mV
20ns      1.275V     1.632V     949mV
[Falling Waveform]
R_fixture= 50.000
V_fixture= 0.0
V_fixture_min= 0.0
V_fixture_max= 0.0
|time   V(typ)   V(min)   V(max)
0s        1.956V     1.547V     2.498V
526ps     1.956V     1.547V     2.479V
676ps     1.956V     1.547V     1.245V
879ps     1.939V     1.547V     260.5mV
1.045ns   1.015V     1.547V     65.88mV
1.257ns   417.6mV    1.547V     23.28mV
1.469ns   117.3mV    1.514V     10.46mV
1.872ns   18.89mV    349.7mV    2.209mV
2.504ns   3.093mV    32.55mV    309.6uV
20ns      72.47nV    114.4nV    217.9nV
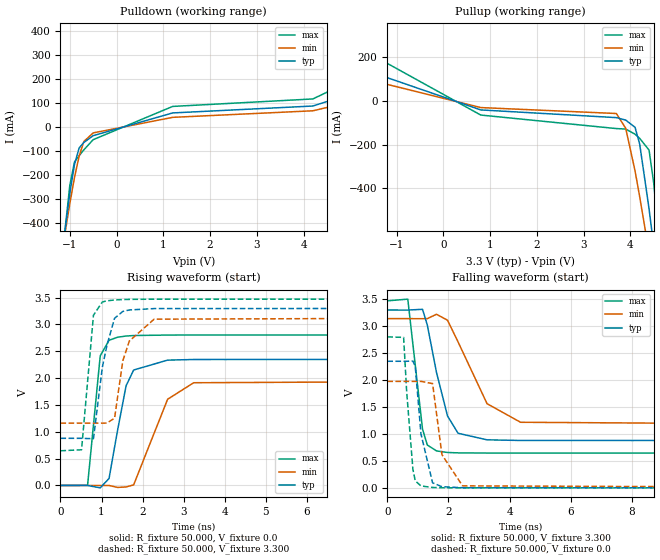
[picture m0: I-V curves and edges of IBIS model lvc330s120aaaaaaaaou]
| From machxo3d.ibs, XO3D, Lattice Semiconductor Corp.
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|   Model lvc330s120aaaaaaaaou
[Model] lvc330s120aaaaaaaaou
Model_type Output
Polarity   Non-Inverting
Enable   Active-High
Vmeas =  1.650V
Cref =  0.0F
Rref =  1.000M
Vref =  0.0V
C_comp   4.200pF   3.800pF   7.500pF
[Temperature Range]   25.000   0.105k   -40.000
[Voltage Range]   3.300V   3.140V   3.470V
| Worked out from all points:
|   slope of the pulldown table from 0 to 0.495 V, typ, clamps not added: 16.2 ohm
|   slope of the pullup table from 0 to 0.495 V, typ, clamps not added: 17.8 ohm
|   rising waveform, R_fixture 50.000, V_fixture 0.0: 20-80 % time 333ps typ, 561ps min, 178ps max; typ from 0 V to 2.35 V
|   rising waveform, R_fixture 50.000, V_fixture 3.300: 20-80 % time 295ps typ, 344ps min, 191ps max; typ from 0.878 V to 3.3 V
|   falling waveform, R_fixture 50.000, V_fixture 3.300: 20-80 % time 568ps typ, 984ps min, 312ps max; typ from 3.3 V to 0.878 V
|   falling waveform, R_fixture 50.000, V_fixture 0.0: 20-80 % time 303ps typ, 360ps min, 209ps max; typ from 2.35 V to 0 V
[Pulldown]
|Voltage   I(typ)   I(min)   I(max)
-3.3V     -4.507A    -3.483A    -6.263A
-1.1V     -426.7mA   -439.1mA   -425mA
-1V       -276.1mA   -319.1mA   -243.2mA
-900mV    -156.2mA   -210.3mA   -145.7mA
-800mV    -87.54mA   -121.3mA   -119.5mA
-700mV    -64.61mA   -60.71mA   -95.41mA
-500mV    -36.31mA   -24.81mA   -52.97mA
1.2V      58.2mA     39.81mA    85.22mA
4.2V      86.92mA    67.08mA    116.3mA
5.1V      142.2mA    108.1mA    199.8mA
6.4V      278.1mA    199.6mA    418.1mA
6.6V      304.4mA    216.1mA    461.1mA
[Pullup]
|Voltage   I(typ)   I(min)   I(max)
-3.3V     202.4mA    139.1mA    333.1mA
-2.4V     194.7mA    139.1mA    313.5mA
800mV     -41.29mA   -30.53mA   -64.86mA
3.7V      -76.51mA   -57.72mA   -126.6mA
3.9V      -87.81mA   -125.4mA   -128.9mA
4.1V      -120.9mA   -320.5mA   -152.3mA
4.2V      -198.5mA   -439.5mA   -171.8mA
4.4V      -494.9mA   -694.9mA   -225.2mA
4.5V      -665.4mA   -827.4mA   -377.2mA
4.6V      -841.6mA   -961.9mA   -601.4mA
4.7V      -1.021A    -1.098A    -846.9mA
6.6V      -4.589A    -3.768A    -5.939A
[Ramp]
| variable   typ   min   max
dV/dt_r   1.409/0.331n   1.186/0.559n   1.681/0.177n
dV/dt_f   1.453/0.569n   1.187/0.988n   1.695/0.311n
R_load = 50.000
[Rising Waveform]
R_fixture= 50.000
V_fixture= 0.0
V_fixture_min= 0.0
V_fixture_max= 0.0
|time   V(typ)   V(min)   V(max)
0s        13.28nV    34.6nV     153.1nV
661ps     271.1uV    -7.132uV   4.271mV
969ps     -44.44mV   129.5uV    2.414V
1.184ns   131.3mV    -227.1uV   2.704V
1.392ns   1.03V      -36.35mV   2.761V
1.599ns   1.857V     -27.57mV   2.783V
1.783ns   2.15V      11.21mV    2.792V
2.61ns    2.334V     1.605V     2.801V
3.245ns   2.346V     1.913V     2.802V
20ns      2.349V     1.976V     2.802V
[Rising Waveform]
R_fixture= 50.000
V_fixture= 3.300
V_fixture_min= 3.140
V_fixture_max= 3.470
|time   V(typ)   V(min)   V(max)
0s        878.1mV    1.161V     645.8mV
514ps     878.1mV    1.161V     665.1mV
804ps     870.6mV    1.161V     3.17V
1.02ns    2.201V     1.161V     3.417V
1.13ns    2.601V     1.162V     3.438V
1.318ns   3.113V     1.253V     3.454V
1.519ns   3.241V     2.32V      3.462V
1.677ns   3.268V     2.689V     3.465V
2.282ns   3.294V     3.097V     3.469V
20ns      3.3V       3.14V      3.47V
[Falling Waveform]
R_fixture= 50.000
V_fixture= 3.300
V_fixture_min= 3.140
V_fixture_max= 3.470
|time   V(typ)   V(min)   V(max)
0s        3.3V       3.14V      3.47V
669ps     3.299V     3.14V      3.502V
1.151ns   3.313V     3.139V     1.09V
1.307ns   3.023V     3.14V      795mV
1.608ns   2.142V     3.221V     685.8mV
1.969ns   1.333V     3.11V      656.6mV
2.313ns   1.013V     2.708V     649.2mV
3.261ns   891.2mV    1.562V     646mV
4.356ns   879.5mV    1.217V     645.8mV
20ns      878.1mV    1.161V     645.8mV
[Falling Waveform]
R_fixture= 50.000
V_fixture= 0.0
V_fixture_min= 0.0
V_fixture_max= 0.0
|time   V(typ)   V(min)   V(max)
0s        2.349V     1.976V     2.802V
533ps     2.349V     1.976V     2.792V
634ps     2.349V     1.976V     1.772V
837ps     2.353V     1.976V     341.5mV
913ps     2.257V     1.976V     129.6mV
1.099ns   1.004V     1.976V     35.59mV
1.48ns    93.81mV    1.935V     7.425mV
1.786ns   21.37mV    615.1mV    2.308mV
2.462ns   2.927mV    36.93mV    330.1uV
20ns      59.93nV    179.9nV    169.9nV
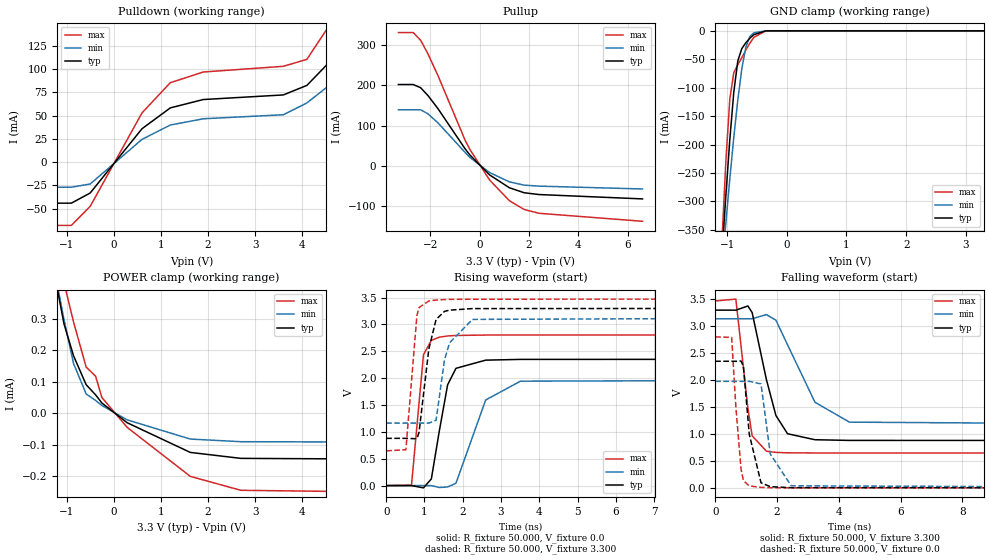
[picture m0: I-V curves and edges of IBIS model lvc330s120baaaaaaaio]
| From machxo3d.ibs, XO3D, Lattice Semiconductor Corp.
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|   Model lvc330s120baaaaaaaio
[Model] lvc330s120baaaaaaaio
Model_type I/O
Polarity   Non-Inverting
Enable   Active-Low
Vinl =  0.800V
Vinh =  2.000V
Vmeas =  1.650V
Cref =  0.0F
Rref =  1.000M
Vref =  0.0V
C_comp   4.200pF   3.800pF   7.500pF
[Temperature Range]   25.000   0.105k   -40.000
[Voltage Range]   3.300V   3.140V   3.470V
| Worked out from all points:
|   slope of the pulldown table from 0 to 0.495 V, typ, clamps not added: 16.2 ohm
|   slope of the pullup table from 0 to 0.495 V, typ, clamps not added: 17.8 ohm
|   GND clamp passes 1 mA (typ) near -0.43 V on its own axis
|   POWER clamp passes 1 mA (typ) near -1.85 V on its own axis
|   rising waveform, R_fixture 50.000, V_fixture 0.0: 20-80 % time 332ps typ, 560ps min, 178ps max; typ from 0.002 V to 2.35 V
|   rising waveform, R_fixture 50.000, V_fixture 3.300: 20-80 % time 292ps typ, 345ps min, 191ps max; typ from 0.88 V to 3.3 V
|   falling waveform, R_fixture 50.000, V_fixture 3.300: 20-80 % time 570ps typ, 995ps min, 312ps max; typ from 3.3 V to 0.88 V
|   falling waveform, R_fixture 50.000, V_fixture 0.0: 20-80 % time 304ps typ, 362ps min, 210ps max; typ from 2.35 V to 0.002 V
[Pulldown]
|Voltage   I(typ)   I(min)   I(max)
-3.3V     -43.98mA   -26.85mA   -67.81mA
-900mV    -43.98mA   -26.85mA   -67.81mA
-500mV    -33.06mA   -23.42mA   -47.39mA
600mV     35.86mA    24.47mA    52.84mA
1.2V      58.2mA     39.81mA    85.22mA
1.9V      67.18mA    46.53mA    96.69mA
3.6V      72.12mA    50.88mA    102.8mA
4.1V      82.35mA    63.56mA    110.3mA
4.7V      113.7mA    87.4mA     156.2mA
5.3V      158.2mA    119.7mA    224.9mA
5.9V      217.5mA    160.8mA    319.3mA
6.6V      303.6mA    218.1mA    456.6mA
[Pullup]
|Voltage   I(typ)   I(min)   I(max)
-3.3V     202.3mA    139.4mA    331.8mA
-2.7V     202.3mA    139.4mA    331.8mA
-2.4V     194.4mA    139.4mA    312.7mA
-2.1V     174.7mA    129.1mA    278.4mA
-1.7V     142.5mA    107mA      225.1mA
-600mV    42.45mA    33.31mA    64.19mA
-400mV    26.61mA    20.5mA     40.39mA
400mV     -23.03mA   -17.17mA   -35.88mA
1.2V      -54.99mA   -40.25mA   -87.25mA
1.8V      -67.47mA   -48.45mA   -109.2mA
2.4V      -71.91mA   -50.95mA   -118.6mA
6.6V      -82.78mA   -58.05mA   -138.6mA
[GND_clamp]
|Voltage   I(typ)   I(min)   I(max)
-3.3V     -4.506A    -3.482A    -6.262A
-1.089V   -398.3mA   -420.5mA   -374.5mA
-1.022V   -290.6mA   -338.5mA   -230.4mA
-955mV    -191.2mA   -260.1mA   -119.8mA
-888mV    -107.4mA   -186.9mA   -73.47mA
-821mV    -52.87mA   -121.3mA   -59.62mA
-754mV    -31.28mA   -66.86mA   -47.24mA
-687mV    -21.04mA   -28.74mA   -34.02mA
-620mV    -13.09mA   -10.15mA   -21.79mA
-553mV    -6.755mA   -3.505mA   -11.52mA
-352mV    -90.18uA   -45.39uA   -119.9uA
3.3V      0A         0A         0A
[POWER_clamp]
|Voltage   I(typ)   I(min)   I(max)
-3.3V     3.967mA    2.512mA    11.53mA
-1.323V   507.3uA    506.4uA    605.6uA
-1.189V   387.7uA    399.8uA    501.1uA
-1.055V   282.8uA    296.7uA    413.8uA
-854mV    182.6uA    158.2uA    289.7uA
-586mV    90.73uA    61.33uA    146.6uA
-385mV    58.36uA    40.66uA    117.5uA
-251mV    32.53uA    24.74uA    49.87uA
285mV     -29.95uA   -20.85uA   -44.72uA
1.625V    -124uA     -81.72uA   -199.9uA
2.697V    -142.9uA   -90.03uA   -244.1uA
6.6V      -145.9uA   -91.75uA   -251.2uA
[Ramp]
| variable   typ   min   max
dV/dt_r   1.409/0.331n   1.186/0.559n   1.681/0.177n
dV/dt_f   1.452/0.571n   1.186/0.990n   1.693/0.313n
R_load = 50.000
[Rising Waveform]
R_fixture= 50.000
V_fixture= 0.0
V_fixture_min= 0.0
V_fixture_max= 0.0
|time   V(typ)   V(min)   V(max)
0s        1.574mV    1.318mV    1.97mV
661ps     1.852mV    1.311mV    10.57mV
974ps     -40.58mV   1.456mV    2.435V
1.18ns    126.3mV    1.082mV    2.703V
1.387ns   1.012V     -33.87mV   2.762V
1.605ns   1.876V     -23.93mV   2.785V
1.823ns   2.183V     44.62mV    2.794V
2.599ns   2.335V     1.594V     2.802V
3.509ns   2.349V     1.944V     2.803V
20ns      2.351V     1.978V     2.803V
[Rising Waveform]
R_fixture= 50.000
V_fixture= 3.300
V_fixture_min= 3.140
V_fixture_max= 3.470
|time   V(typ)   V(min)   V(max)
0s        880.5mV    1.164V     648.5mV
514ps     880.5mV    1.164V     668.2mV
803ps     872.7mV    1.164V     3.168V
858ps     992mV      1.164V     3.314V
1.114ns   2.542V     1.164V     3.435V
1.303ns   3.091V     1.215V     3.453V
1.522ns   3.242V     2.333V     3.462V
1.656ns   3.265V     2.657V     3.465V
2.253ns   3.294V     3.093V     3.469V
20ns      3.3V       3.14V      3.47V
[Falling Waveform]
R_fixture= 50.000
V_fixture= 3.300
V_fixture_min= 3.140
V_fixture_max= 3.470
|time   V(typ)   V(min)   V(max)
0s        3.3V       3.14V      3.47V
668ps     3.299V     3.14V      3.504V
1.058ns   3.377V     3.14V      1.479V
1.196ns   3.254V     3.14V      967.2mV
1.657ns   2.011V     3.217V     682mV
1.965ns   1.344V     3.113V     659.4mV
2.34ns    1.006V     2.658V     651.9mV
3.228ns   894.5mV    1.59V      648.8mV
4.345ns   881.9mV    1.221V     648.6mV
20ns      880.4mV    1.163V     648.5mV
[Falling Waveform]
R_fixture= 50.000
V_fixture= 0.0
V_fixture_min= 0.0
V_fixture_max= 0.0
|time   V(typ)   V(min)   V(max)
0s        2.351V     1.978V     2.803V
533ps     2.351V     1.978V     2.793V
669ps     2.35V      1.978V     1.494V
837ps     2.355V     1.978V     348.8mV
914ps     2.254V     1.978V     132.2mV
1.102ns   997mV      1.978V     37.41mV
1.483ns   95.25mV    1.93V      9.595mV
1.782ns   23.5mV     628.7mV    4.402mV
2.462ns   4.516mV    39.5mV     2.24mV
20ns      1.574mV    1.318mV    1.97mV
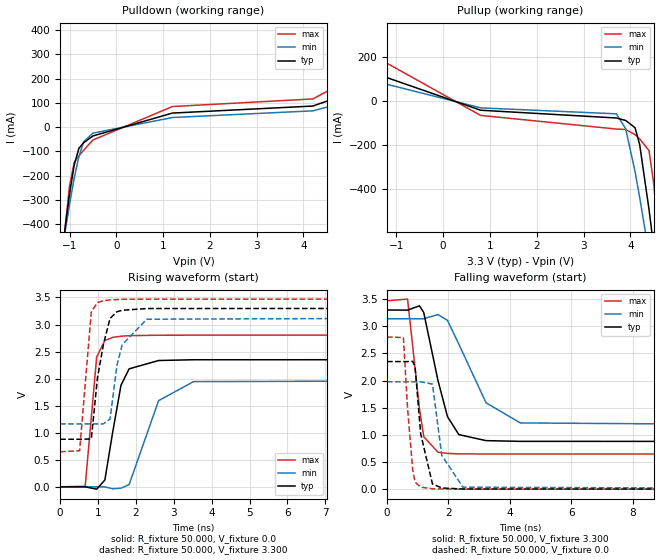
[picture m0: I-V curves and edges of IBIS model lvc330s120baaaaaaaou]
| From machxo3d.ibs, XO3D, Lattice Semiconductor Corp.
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|   Model lvc330s120baaaaaaaou
[Model] lvc330s120baaaaaaaou
Model_type Output
Polarity   Non-Inverting
Enable   Active-High
Vmeas =  1.650V
Cref =  0.0F
Rref =  1.000M
Vref =  0.0V
C_comp   4.200pF   3.800pF   7.500pF
[Temperature Range]   25.000   0.105k   -40.000
[Voltage Range]   3.300V   3.140V   3.470V
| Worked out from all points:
|   slope of the pulldown table from 0 to 0.495 V, typ, clamps not added: 16.2 ohm
|   slope of the pullup table from 0 to 0.495 V, typ, clamps not added: 17.8 ohm
|   rising waveform, R_fixture 50.000, V_fixture 0.0: 20-80 % time 332ps typ, 559ps min, 178ps max; typ from 0.002 V to 2.35 V
|   rising waveform, R_fixture 50.000, V_fixture 3.300: 20-80 % time 292ps typ, 342ps min, 191ps max; typ from 0.88 V to 3.3 V
|   falling waveform, R_fixture 50.000, V_fixture 3.300: 20-80 % time 571ps typ, 990ps min, 312ps max; typ from 3.3 V to 0.88 V
|   falling waveform, R_fixture 50.000, V_fixture 0.0: 20-80 % time 305ps typ, 361ps min, 210ps max; typ from 2.35 V to 0.002 V
[Pulldown]
|Voltage   I(typ)   I(min)   I(max)
-3.3V     -4.507A    -3.483A    -6.263A
-1.1V     -426.7mA   -439.1mA   -425.1mA
-1V       -276.1mA   -319.1mA   -243.3mA
-900mV    -156.3mA   -210.4mA   -145.7mA
-800mV    -87.59mA   -121.4mA   -119.6mA
-700mV    -64.68mA   -60.75mA   -95.51mA
-500mV    -36.41mA   -24.89mA   -53.12mA
1.2V      58.06mA    39.72mA    84.98mA
4.2V      87.02mA    67.25mA    116.4mA
5.4V      168.2mA    127.3mA    240.1mA
6.4V      280.6mA    203.6mA    420.2mA
6.6V      307.4mA    220.9mA    463.7mA
[Pullup]
|Voltage   I(typ)   I(min)   I(max)
-3.3V     204mA      140.9mA    334.7mA
-2.4V     195.9mA    140.9mA    314.6mA
800mV     -41.36mA   -30.58mA   -64.97mA
3.7V      -76.63mA   -57.78mA   -126.9mA
3.9V      -87.87mA   -125.4mA   -129.1mA
4.1V      -120.9mA   -320.5mA   -152.3mA
4.2V      -198.5mA   -439.5mA   -171.8mA
4.4V      -494.9mA   -694.9mA   -225.3mA
4.5V      -665.5mA   -827.4mA   -377.3mA
4.6V      -841.6mA   -961.9mA   -601.4mA
4.7V      -1.021A    -1.098A    -846.9mA
6.6V      -4.589A    -3.768A    -5.939A
[Ramp]
| variable   typ   min   max
dV/dt_r   1.409/0.331n   1.186/0.559n   1.681/0.177n
dV/dt_f   1.452/0.571n   1.186/0.990n   1.693/0.313n
R_load = 50.000
[Rising Waveform]
R_fixture= 50.000
V_fixture= 0.0
V_fixture_min= 0.0
V_fixture_max= 0.0
|time   V(typ)   V(min)   V(max)
0s        1.574mV    1.318mV    1.97mV
661ps     1.859mV    1.31mV     10.57mV
964ps     -41.68mV   1.455mV    2.399V
1.18ns    126.3mV    1.09mV     2.704V
1.387ns   1.012V     -34.03mV   2.762V
1.605ns   1.876V     -23.94mV   2.784V
1.82ns    2.181V     41.9mV     2.794V
2.599ns   2.335V     1.594V     2.802V
3.52ns    2.349V     1.945V     2.803V
20ns      2.351V     1.978V     2.803V
[Rising Waveform]
R_fixture= 50.000
V_fixture= 3.300
V_fixture_min= 3.140
V_fixture_max= 3.470
|time   V(typ)   V(min)   V(max)
0s        880.5mV    1.164V     648.5mV
514ps     880.5mV    1.164V     668.2mV
822ps     885.9mV    1.164V     3.235V
986ps     2.022V     1.163V     3.407V
1.143ns   2.635V     1.164V     3.439V
1.317ns   3.113V     1.253V     3.454V
1.5ns     3.236V     2.251V     3.461V
1.638ns   3.263V     2.627V     3.465V
2.287ns   3.295V     3.098V     3.469V
20ns      3.3V       3.14V      3.47V
[Falling Waveform]
R_fixture= 50.000
V_fixture= 3.300
V_fixture_min= 3.140
V_fixture_max= 3.470
|time   V(typ)   V(min)   V(max)
0s        3.3V       3.14V      3.47V
669ps     3.299V     3.14V      3.502V
1.058ns   3.377V     3.14V      1.479V
1.196ns   3.254V     3.14V      967.2mV
1.661ns   2V         3.216V     681.8mV
1.969ns   1.338V     3.11V      659.9mV
2.339ns   1.006V     2.673V     651.8mV
3.226ns   894.8mV    1.591V     648.8mV
4.345ns   881.8mV    1.221V     648.5mV
20ns      880.4mV    1.163V     648.5mV
[Falling Waveform]
R_fixture= 50.000
V_fixture= 0.0
V_fixture_min= 0.0
V_fixture_max= 0.0
|time   V(typ)   V(min)   V(max)
0s        2.351V     1.978V     2.803V
533ps     2.351V     1.978V     2.793V
669ps     2.35V      1.978V     1.494V
837ps     2.355V     1.978V     348.7mV
914ps     2.254V     1.978V     132.2mV
1.096ns   1.022V     1.978V     38.26mV
1.48ns    96.96mV    1.937V     9.281mV
1.784ns   23.43mV    624.2mV    4.533mV
2.473ns   4.424mV    37.53mV    2.275mV
20ns      1.574mV    1.318mV    1.97mV
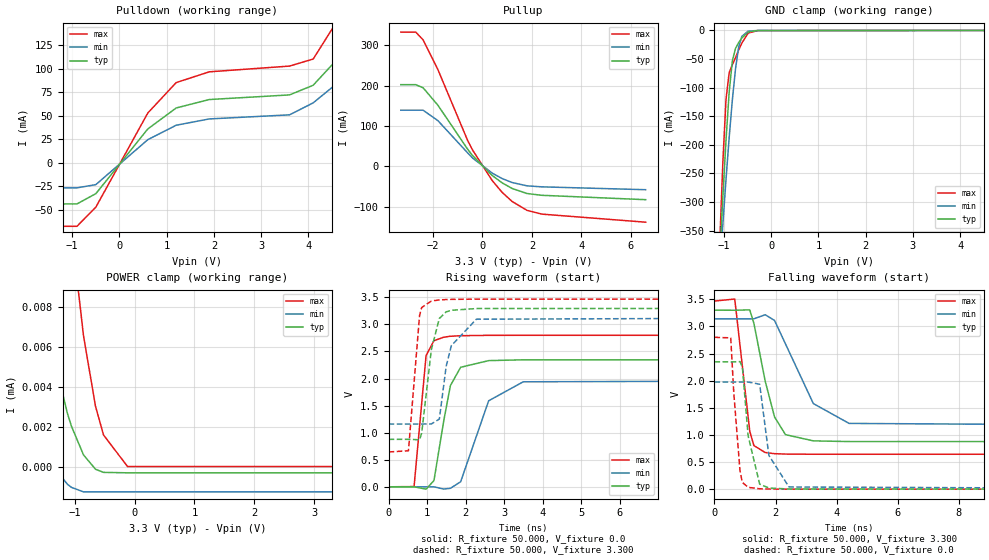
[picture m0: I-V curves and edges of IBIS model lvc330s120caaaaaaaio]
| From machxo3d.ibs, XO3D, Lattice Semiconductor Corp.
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|   Model lvc330s120caaaaaaaio
[Model] lvc330s120caaaaaaaio
Model_type I/O
Polarity   Non-Inverting
Enable   Active-Low
Vinl =  0.800V
Vinh =  2.000V
Vmeas =  1.650V
Cref =  0.0F
Rref =  1.000M
Vref =  0.0V
C_comp   4.200pF   3.800pF   7.500pF
[Temperature Range]   25.000   0.105k   -40.000
[Voltage Range]   3.300V   3.140V   3.470V
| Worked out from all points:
|   slope of the pulldown table from 0 to 0.495 V, typ, clamps not added: 16.2 ohm
|   slope of the pullup table from 0 to 0.495 V, typ, clamps not added: 17.8 ohm
|   GND clamp passes 1 mA (typ) near -0.43 V on its own axis
|   rising waveform, R_fixture 50.000, V_fixture 0.0: 20-80 % time 332ps typ, 559ps min, 178ps max; typ from 0 V to 2.35 V
|   rising waveform, R_fixture 50.000, V_fixture 3.300: 20-80 % time 295ps typ, 346ps min, 192ps max; typ from 0.876 V to 3.3 V
|   falling waveform, R_fixture 50.000, V_fixture 3.300: 20-80 % time 570ps typ, 991ps min, 310ps max; typ from 3.3 V to 0.876 V
|   falling waveform, R_fixture 50.000, V_fixture 0.0: 20-80 % time 302ps typ, 361ps min, 208ps max; typ from 2.35 V to 0 V
[Pulldown]
|Voltage   I(typ)   I(min)   I(max)
-3.3V     -43.98mA   -26.85mA   -67.81mA
-900mV    -43.98mA   -26.85mA   -67.81mA
-500mV    -33.06mA   -23.42mA   -47.39mA
600mV     35.86mA    24.47mA    52.84mA
1.2V      58.2mA     39.81mA    85.22mA
1.9V      67.18mA    46.53mA    96.69mA
3.6V      72.12mA    50.88mA    102.8mA
4.1V      82.4mA     63.66mA    110.3mA
4.8V      120.5mA    92.36mA    166.2mA
5.4V      167.4mA    125.9mA    239.5mA
6V        229mA      167.7mA    338.3mA
6.6V      303.8mA    215.6mA    460.4mA
[Pullup]
|Voltage   I(typ)   I(min)   I(max)
-3.3V     202.4mA    139.1mA    332.8mA
-2.7V     202.4mA    139.1mA    332.8mA
-2.4V     194.7mA    139.1mA    313.5mA
-1.8V     151.3mA    113.1mA    239.5mA
-600mV    42.46mA    33.32mA    64.18mA
-400mV    26.61mA    20.5mA     40.38mA
400mV     -23.03mA   -17.17mA   -35.88mA
800mV     -41.29mA   -30.53mA   -64.86mA
1.2V      -54.99mA   -40.25mA   -87.25mA
1.8V      -67.47mA   -48.45mA   -109.2mA
2.4V      -71.91mA   -50.95mA   -118.6mA
6.6V      -82.78mA   -58.05mA   -138.6mA
[GND_clamp]
|Voltage   I(typ)   I(min)   I(max)
-3.3V     -4.507A    -3.482A    -6.263A
-1.089V   -398.4mA   -420.6mA   -374.7mA
-1.022V   -290.7mA   -338.6mA   -230.6mA
-955mV    -191.4mA   -260.2mA   -120.1mA
-888mV    -107.5mA   -187mA     -73.7mA
-821mV    -53mA      -121.4mA   -59.85mA
-754mV    -31.41mA   -66.94mA   -47.47mA
-687mV    -21.17mA   -28.82mA   -34.25mA
-620mV    -13.21mA   -10.23mA   -22mA
-486mV    -2.63mA    -1.112mA   -4.479mA
-285mV    -80.91uA   -42.41uA   -152.3uA
6.6V      121.2uA    55.82uA    291.2uA
[POWER_clamp]
|Voltage   I(typ)   I(min)   I(max)
-3.3V     704.7uA    440.9uA    1.167mA
-2.596V   46.79uA    12.42uA    184.2uA
-2.328V   25.67uA    8.107uA    76.87uA
-1.792V   13.09uA    2.762uA    43.68uA
-1.39V    5.98uA     124.1nA    24.26uA
-1.122V   2.656uA    -886.1nA   13.98uA
-1.055V   2.02uA     -1.042uA   11.85uA
-854mV    585.6nA    -1.267uA   6.557uA
-653mV    -133.8nA   -1.267uA   3.017uA
-519mV    -290.6nA   -1.267uA   1.58uA
-117mV    -313.6nA   -1.267uA   0A
3.3V      -313.6nA   -1.267uA   0A
[Ramp]
| variable   typ   min   max
dV/dt_r   1.408/0.332n   1.185/0.559n   1.680/0.178n
dV/dt_f   1.453/0.569n   1.188/0.987n   1.695/0.311n
R_load = 50.000
[Rising Waveform]
R_fixture= 50.000
V_fixture= 0.0
V_fixture_min= 0.0
V_fixture_max= 0.0
|time   V(typ)   V(min)   V(max)
0s        13.01nV    34.25nV    147.9nV
661ps     278.5uV    -5.376uV   4.618mV
973ps     -43.48mV   131.9uV    2.424V
1.178ns   116mV      -230.2uV   2.699V
1.433ns   1.223V     -41.5mV    2.764V
1.605ns   1.87V      -27.17mV   2.781V
1.871ns   2.208V     93.49mV    2.791V
2.598ns   2.331V     1.589V     2.798V
3.497ns   2.346V     1.94V      2.799V
20ns      2.347V     1.975V     2.799V
[Rising Waveform]
R_fixture= 50.000
V_fixture= 3.300
V_fixture_min= 3.140
V_fixture_max= 3.470
|time   V(typ)   V(min)   V(max)
0s        876.5mV    1.16V      643.5mV
515ps     876.5mV    1.16V      665.6mV
804ps     868.9mV    1.16V      3.165V
859ps     992.1mV    1.16V      3.312V
1.11ns    2.535V     1.161V     3.432V
1.318ns   3.111V     1.252V     3.452V
1.495ns   3.232V     2.227V     3.459V
1.629ns   3.26V      2.607V     3.462V
2.279ns   3.293V     3.096V     3.467V
20ns      3.299V     3.139V     3.468V
[Falling Waveform]
R_fixture= 50.000
V_fixture= 3.300
V_fixture_min= 3.140
V_fixture_max= 3.470
|time   V(typ)   V(min)   V(max)
0s        3.299V     3.139V     3.468V
665ps     3.298V     3.139V     3.504V
1.156ns   3.305V     3.139V     1.066V
1.292ns   3.056V     3.14V      803.3mV
1.661ns   1.992V     3.215V     675.6mV
1.967ns   1.332V     3.11V      654.2mV
2.325ns   1.005V     2.678V     646.8mV
3.237ns   890.1mV    1.578V     643.7mV
4.408ns   877.6mV    1.212V     643.5mV
20ns      876.4mV    1.16V      643.5mV
[Falling Waveform]
R_fixture= 50.000
V_fixture= 0.0
V_fixture_min= 0.0
V_fixture_max= 0.0
|time   V(typ)   V(min)   V(max)
0s        2.347V     1.975V     2.799V
533ps     2.347V     1.975V     2.789V
634ps     2.347V     1.975V     1.765V
837ps     2.351V     1.975V     335.1mV
914ps     2.25V      1.975V     125.1mV
1.103ns   983.6mV    1.975V     34.04mV
1.48ns    92.67mV    1.934V     7.57mV
1.782ns   21.25mV    622.6mV    2.389mV
2.44ns    3.061mV    40.26mV    241.1uV
20ns      55.11nV    174nV      157nV
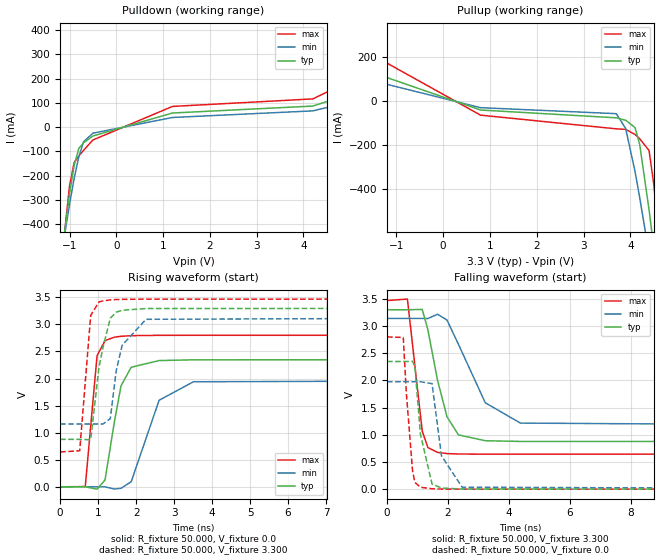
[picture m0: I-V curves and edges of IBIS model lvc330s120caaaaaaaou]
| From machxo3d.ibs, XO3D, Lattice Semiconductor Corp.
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|   Model lvc330s120caaaaaaaou
[Model] lvc330s120caaaaaaaou
Model_type Output
Polarity   Non-Inverting
Enable   Active-High
Vmeas =  1.650V
Cref =  0.0F
Rref =  1.000M
Vref =  0.0V
C_comp   4.200pF   3.800pF   7.500pF
[Temperature Range]   25.000   0.105k   -40.000
[Voltage Range]   3.300V   3.140V   3.470V
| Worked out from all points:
|   slope of the pulldown table from 0 to 0.495 V, typ, clamps not added: 16.2 ohm
|   slope of the pullup table from 0 to 0.495 V, typ, clamps not added: 17.8 ohm
|   rising waveform, R_fixture 50.000, V_fixture 0.0: 20-80 % time 333ps typ, 561ps min, 178ps max; typ from 0 V to 2.35 V
|   rising waveform, R_fixture 50.000, V_fixture 3.300: 20-80 % time 295ps typ, 344ps min, 192ps max; typ from 0.876 V to 3.3 V
|   falling waveform, R_fixture 50.000, V_fixture 3.300: 20-80 % time 568ps typ, 987ps min, 310ps max; typ from 3.3 V to 0.876 V
|   falling waveform, R_fixture 50.000, V_fixture 0.0: 20-80 % time 302ps typ, 360ps min, 208ps max; typ from 2.35 V to 0 V
[Pulldown]
|Voltage   I(typ)   I(min)   I(max)
-3.3V     -4.507A    -3.483A    -6.263A
-1.1V     -426.7mA   -439.1mA   -425mA
-1V       -276.1mA   -319.1mA   -243.3mA
-900mV    -156.3mA   -210.4mA   -145.7mA
-800mV    -87.58mA   -121.4mA   -119.6mA
-700mV    -64.66mA   -60.74mA   -95.48mA
-500mV    -36.38mA   -24.87mA   -53.08mA
1.2V      58.29mA    39.84mA    85.45mA
4.2V      87.01mA    67.13mA    116.5mA
5.1V      142.3mA    108.1mA    200.1mA
6.4V      278.3mA    199.7mA    418.5mA
6.6V      304.7mA    216.2mA    461.6mA
[Pullup]
|Voltage   I(typ)   I(min)   I(max)
-3.3V     202.6mA    139.2mA    333.4mA
-2.4V     194.8mA    139.2mA    313.9mA
800mV     -41.18mA   -30.49mA   -64.61mA
3.7V      -76.59mA   -57.76mA   -126.7mA
3.9V      -87.85mA   -125.4mA   -129mA
4.1V      -120.9mA   -320.5mA   -152.3mA
4.2V      -198.5mA   -439.5mA   -171.8mA
4.4V      -494.9mA   -694.9mA   -225.3mA
4.5V      -665.5mA   -827.4mA   -377.2mA
4.6V      -841.6mA   -961.9mA   -601.4mA
4.7V      -1.021A    -1.098A    -846.9mA
6.6V      -4.589A    -3.768A    -5.939A
[Ramp]
| variable   typ   min   max
dV/dt_r   1.408/0.332n   1.185/0.559n   1.680/0.178n
dV/dt_f   1.453/0.569n   1.188/0.987n   1.695/0.311n
R_load = 50.000
[Rising Waveform]
R_fixture= 50.000
V_fixture= 0.0
V_fixture_min= 0.0
V_fixture_max= 0.0
|time   V(typ)   V(min)   V(max)
0s        13.01nV    34.25nV    147.9nV
661ps     269.2uV    -7.147uV   4.618mV
972ps     -43.49mV   129.4uV    2.421V
1.182ns   126.2mV    -228.5uV   2.701V
1.43ns    1.209V     -41.42mV   2.764V
1.603ns   1.865V     -27.18mV   2.78V
1.871ns   2.208V     93.5mV     2.792V
2.606ns   2.332V     1.599V     2.798V
3.512ns   2.346V     1.941V     2.799V
20ns      2.347V     1.975V     2.799V
[Rising Waveform]
R_fixture= 50.000
V_fixture= 3.300
V_fixture_min= 3.140
V_fixture_max= 3.470
|time   V(typ)   V(min)   V(max)
0s        876.5mV    1.16V      643.5mV
515ps     876.5mV    1.16V      665.6mV
804ps     868.9mV    1.16V      3.165V
1.021ns   2.202V     1.16V      3.415V
1.13ns    2.581V     1.161V     3.435V
1.32ns    3.114V     1.259V     3.452V
1.475ns   3.226V     2.139V     3.459V
1.633ns   3.261V     2.615V     3.462V
2.261ns   3.293V     3.094V     3.467V
20ns      3.299V     3.139V     3.468V
[Falling Waveform]
R_fixture= 50.000
V_fixture= 3.300
V_fixture_min= 3.140
V_fixture_max= 3.470
|time   V(typ)   V(min)   V(max)
0s        3.299V     3.139V     3.468V
669ps     3.298V     3.139V     3.495V
1.155ns   3.305V     3.139V     1.069V
1.34ns    2.932V     3.137V     765.8mV
1.657ns   2.003V     3.216V     676.5mV
1.967ns   1.332V     3.11V      654.2mV
2.343ns   998.4mV    2.664V     646.5mV
3.223ns   890.7mV    1.589V     643.7mV
4.376ns   877.7mV    1.215V     643.5mV
20ns      876.4mV    1.16V      643.5mV
[Falling Waveform]
R_fixture= 50.000
V_fixture= 0.0
V_fixture_min= 0.0
V_fixture_max= 0.0
|time   V(typ)   V(min)   V(max)
0s        2.347V     1.975V     2.799V
533ps     2.347V     1.975V     2.789V
634ps     2.347V     1.975V     1.765V
837ps     2.351V     1.975V     335.1mV
914ps     2.25V      1.975V     125mV
1.097ns   1.008V     1.975V     34.97mV
1.477ns   94.29mV    1.94V      7.242mV
1.786ns   21.23mV    613.6mV    2.205mV
2.465ns   2.891mV    36.19mV    281.1uV
20ns      54.25nV    174.1nV    158.4nV
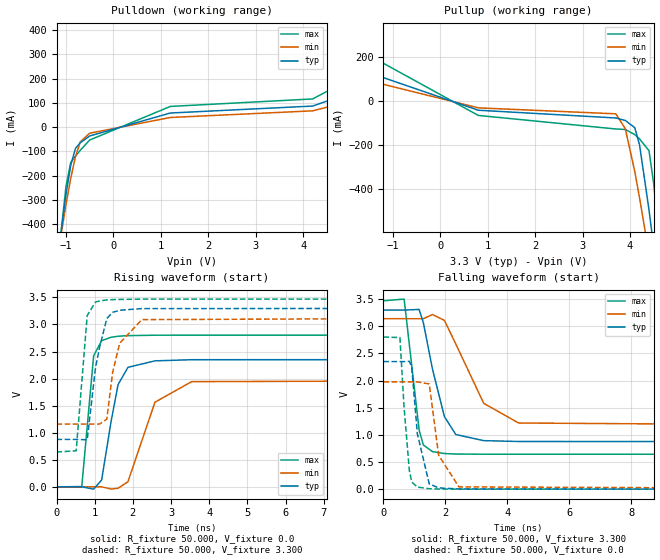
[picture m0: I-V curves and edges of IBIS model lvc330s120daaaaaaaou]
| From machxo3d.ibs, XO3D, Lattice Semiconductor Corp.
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|   Model lvc330s120daaaaaaaou
[Model] lvc330s120daaaaaaaou
Model_type Output
Polarity   Non-Inverting
Enable   Active-High
Vmeas =  1.650V
Cref =  0.0F
Rref =  1.000M
Vref =  0.0V
C_comp   4.200pF   3.800pF   7.500pF
[Temperature Range]   25.000   0.105k   -40.000
[Voltage Range]   3.300V   3.140V   3.470V
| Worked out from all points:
|   slope of the pulldown table from 0 to 0.495 V, typ, clamps not added: 16.2 ohm
|   slope of the pullup table from 0 to 0.495 V, typ, clamps not added: 17.8 ohm
|   rising waveform, R_fixture 50.000, V_fixture 0.0: 20-80 % time 333ps typ, 563ps min, 179ps max; typ from 0 V to 2.35 V
|   rising waveform, R_fixture 50.000, V_fixture 3.300: 20-80 % time 296ps typ, 346ps min, 192ps max; typ from 0.876 V to 3.3 V
|   falling waveform, R_fixture 50.000, V_fixture 3.300: 20-80 % time 573ps typ, 992ps min, 313ps max; typ from 3.3 V to 0.876 V
|   falling waveform, R_fixture 50.000, V_fixture 0.0: 20-80 % time 305ps typ, 364ps min, 210ps max; typ from 2.35 V to 0 V
[Pulldown]
|Voltage   I(typ)   I(min)   I(max)
-3.3V     -4.507A    -3.483A    -6.263A
-1.1V     -426.7mA   -439.1mA   -425mA
-1V       -276.1mA   -319.1mA   -243.3mA
-900mV    -156.3mA   -210.4mA   -145.7mA
-800mV    -87.58mA   -121.4mA   -119.6mA
-700mV    -64.66mA   -60.74mA   -95.48mA
-500mV    -36.38mA   -24.87mA   -53.08mA
1.2V      58.29mA    39.84mA    85.45mA
4.2V      87.02mA    67.25mA    116.4mA
5.4V      168.2mA    127.3mA    240.1mA
6.4V      280.6mA    203.6mA    420.2mA
6.6V      307.4mA    220.9mA    463.7mA
[Pullup]
|Voltage   I(typ)   I(min)   I(max)
-3.3V     204mA      140.9mA    334.7mA
-2.4V     195.9mA    140.9mA    314.6mA
800mV     -41.36mA   -30.58mA   -64.97mA
3.7V      -76.59mA   -57.76mA   -126.7mA
3.9V      -87.85mA   -125.4mA   -129mA
4.1V      -120.9mA   -320.5mA   -152.3mA
4.2V      -198.5mA   -439.5mA   -171.8mA
4.4V      -494.9mA   -694.9mA   -225.3mA
4.5V      -665.5mA   -827.4mA   -377.2mA
4.6V      -841.6mA   -961.9mA   -601.4mA
4.7V      -1.021A    -1.098A    -846.9mA
6.6V      -4.589A    -3.768A    -5.939A
[Ramp]
| variable   typ   min   max
dV/dt_r   1.410/0.333n   1.187/0.561n   1.682/0.178n
dV/dt_f   1.454/0.573n   1.188/0.988n   1.696/0.313n
R_load = 50.000
[Rising Waveform]
R_fixture= 50.000
V_fixture= 0.0
V_fixture_min= 0.0
V_fixture_max= 0.0
|time   V(typ)   V(min)   V(max)
0s        13.01nV    34.25nV    147.9nV
661ps     269.5uV    -7.162uV   4.618mV
972ps     -43.49mV   129.4uV    2.421V
1.182ns   126.2mV    -228.5uV   2.701V
1.43ns    1.209V     -41.42mV   2.764V
1.613ns   1.89V      -26.7mV    2.783V
1.871ns   2.208V     93.5mV     2.794V
2.578ns   2.328V     1.563V     2.802V
3.542ns   2.349V     1.944V     2.803V
20ns      2.351V     1.978V     2.803V
[Rising Waveform]
R_fixture= 50.000
V_fixture= 3.300
V_fixture_min= 3.140
V_fixture_max= 3.470
|time   V(typ)   V(min)   V(max)
0s        876.5mV    1.16V      643.5mV
515ps     876.5mV    1.16V      665.6mV
804ps     868.9mV    1.16V      3.165V
1.021ns   2.202V     1.16V      3.415V
1.13ns    2.581V     1.161V     3.435V
1.318ns   3.111V     1.252V     3.454V
1.471ns   3.225V     2.12V      3.46V
1.657ns   3.264V     2.656V     3.463V
2.236ns   3.294V     3.09V      3.469V
20ns      3.3V       3.14V      3.47V
[Falling Waveform]
R_fixture= 50.000
V_fixture= 3.300
V_fixture_min= 3.140
V_fixture_max= 3.470
|time   V(typ)   V(min)   V(max)
0s        3.3V       3.14V      3.47V
669ps     3.299V     3.14V      3.502V
1.154ns   3.311V     3.139V     1.087V
1.29ns    3.066V     3.14V      814.3mV
1.584ns   2.214V     3.217V     692.5mV
1.969ns   1.338V     3.11V      656.2mV
2.339ns   1.006V     2.673V     647.1mV
3.24ns    894mV      1.581V     643.7mV
4.365ns   877.9mV    1.219V     643.5mV
20ns      876.4mV    1.16V      643.5mV
[Falling Waveform]
R_fixture= 50.000
V_fixture= 0.0
V_fixture_min= 0.0
V_fixture_max= 0.0
|time   V(typ)   V(min)   V(max)
0s        2.351V     1.978V     2.803V
533ps     2.351V     1.978V     2.793V
669ps     2.35V      1.978V     1.494V
837ps     2.355V     1.978V     348.7mV
914ps     2.254V     1.978V     132.2mV
1.096ns   1.022V     1.978V     38.26mV
1.48ns    96.96mV    1.937V     8.506mV
1.784ns   23.43mV    624.2mV    2.549mV
2.439ns   4.044mV    42.47mV    305.9uV
20ns      52.69nV    173.3nV    159.2nV
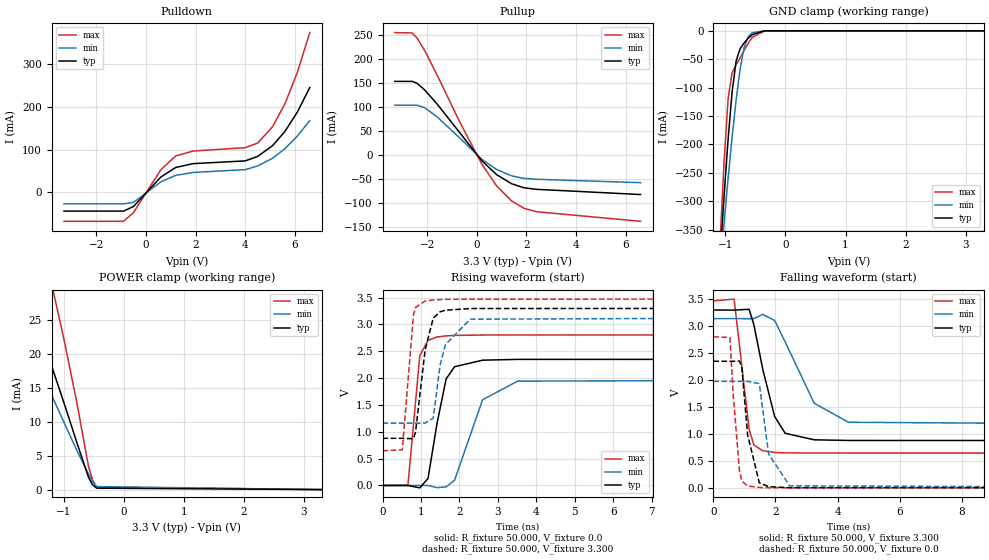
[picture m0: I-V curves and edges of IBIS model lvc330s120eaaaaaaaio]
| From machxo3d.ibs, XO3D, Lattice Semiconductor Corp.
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|   Model lvc330s120eaaaaaaaio
[Model] lvc330s120eaaaaaaaio
Model_type I/O
Polarity   Non-Inverting
Enable   Active-Low
Vinl =  0.800V
Vinh =  2.000V
Vmeas =  1.650V
Cref =  0.0F
Rref =  1.000M
Vref =  0.0V
C_comp   4.200pF   3.800pF   7.500pF
[Temperature Range]   25.000   0.105k   -40.000
[Voltage Range]   3.300V   3.140V   3.470V
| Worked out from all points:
|   slope of the pulldown table from 0 to 0.495 V, typ, clamps not added: 16.2 ohm
|   slope of the pullup table from 0 to 0.495 V, typ, clamps not added: 17.8 ohm
|   GND clamp passes 1 mA (typ) near -0.43 V on its own axis
|   POWER clamp passes 1 mA (typ) near -0.54 V on its own axis
|   rising waveform, R_fixture 50.000, V_fixture 0.0: 20-80 % time 334ps typ, 560ps min, 178ps max; typ from 0 V to 2.35 V
|   rising waveform, R_fixture 50.000, V_fixture 3.300: 20-80 % time 295ps typ, 344ps min, 191ps max; typ from 0.878 V to 3.3 V
|   falling waveform, R_fixture 50.000, V_fixture 3.300: 20-80 % time 568ps typ, 985ps min, 311ps max; typ from 3.3 V to 0.878 V
|   falling waveform, R_fixture 50.000, V_fixture 0.0: 20-80 % time 303ps typ, 360ps min, 209ps max; typ from 2.35 V to 0 V
[Pulldown]
|Voltage   I(typ)   I(min)   I(max)
-3.3V     -43.98mA   -26.85mA   -67.81mA
-900mV    -43.98mA   -26.85mA   -67.81mA
-500mV    -33.06mA   -23.42mA   -47.39mA
600mV     35.86mA    24.47mA    52.84mA
1.2V      58.2mA     39.81mA    85.22mA
1.9V      67.18mA    46.53mA    96.69mA
4V        73.65mA    53.18mA    104.6mA
4.5V      84.05mA    61.72mA    115.3mA
5.1V      109.3mA    79.79mA    153.8mA
5.6V      142.7mA    102.2mA    207.3mA
6.1V      188.2mA    131.9mA    281.1mA
6.6V      245.3mA    168mA      374.1mA
[Pullup]
|Voltage   I(typ)   I(min)   I(max)
-3.3V     153.2mA    103.4mA    255mA
-2.6V     153.2mA    103.4mA    254.2mA
-2.4V     149.1mA    103.4mA    243.2mA
-2.1V     135.5mA    98.29mA    217.7mA
-1.6V     106.2mA    79.33mA    166.7mA
-700mV    47.13mA    35.94mA    70.14mA
200mV     -12.13mA   -9.077mA   -18.82mA
800mV     -41.29mA   -30.53mA   -64.86mA
1.4V      -60.2mA    -43.81mA   -96.07mA
1.9V      -68.67mA   -49.13mA   -111.5mA
2.4V      -71.91mA   -50.95mA   -118.6mA
6.6V      -82.78mA   -58.05mA   -138.6mA
[GND_clamp]
|Voltage   I(typ)   I(min)   I(max)
-3.3V     -4.507A    -3.482A    -6.263A
-1.089V   -398.4mA   -420.6mA   -374.7mA
-1.022V   -290.7mA   -338.6mA   -230.6mA
-955mV    -191.3mA   -260.2mA   -120mA
-888mV    -107.5mA   -187mA     -73.64mA
-821mV    -52.96mA   -121.4mA   -59.79mA
-754mV    -31.36mA   -66.92mA   -47.4mA
-687mV    -21.12mA   -28.79mA   -34.18mA
-620mV    -13.16mA   -10.19mA   -21.93mA
-553mV    -6.814mA   -3.53mA    -11.64mA
-352mV    -96.36uA   -46.21uA   -149.8uA
3.3V      0A         0A         0A
[POWER_clamp]
|Voltage   I(typ)   I(min)   I(max)
-3.3V     59.07mA    46.89mA    89.53mA
-1.993V   37.2mA     28.86mA    58.21mA
-1.926V   35.72mA    27.66mA    56.06mA
-1.591V   27.93mA    21.43mA    44.68mA
-1.189V   17.86mA    13.66mA    29.77mA
-1.122V   16.11mA    12.35mA    27.14mA
-988mV    12.56mA    9.745mA    21.76mA
-787mV    7.078mA    5.887mA    13.07mA
-586mV    1.773mA    2.247mA    3.338mA
-519mV    707uA      1.205mA    1.383mA
-452mV    214.8uA    435.5uA    392.3uA
3.3V      0A         0A         0A
[Ramp]
| variable   typ   min   max
dV/dt_r   1.409/0.331n   1.186/0.559n   1.681/0.177n
dV/dt_f   1.453/0.570n   1.187/0.988n   1.695/0.311n
R_load = 50.000
[Rising Waveform]
R_fixture= 50.000
V_fixture= 0.0
V_fixture_min= 0.0
V_fixture_max= 0.0
|time   V(typ)   V(min)   V(max)
0s        13.28nV    34.6nV     153.1nV
661ps     280.1uV    -5.357uV   4.272mV
969ps     -44.44mV   132uV      2.414V
1.184ns   131.3mV    -222.1uV   2.704V
1.419ns   1.16V      -40.57mV   2.765V
1.655ns   1.984V     -25.98mV   2.786V
1.874ns   2.211V     97.3mV     2.794V
2.603ns   2.333V     1.596V     2.801V
3.518ns   2.348V     1.943V     2.802V
20ns      2.349V     1.976V     2.802V
[Rising Waveform]
R_fixture= 50.000
V_fixture= 3.300
V_fixture_min= 3.140
V_fixture_max= 3.470
|time   V(typ)   V(min)   V(max)
0s        878.1mV    1.161V     645.8mV
514ps     878.1mV    1.161V     665.1mV
804ps     870.6mV    1.161V     3.17V
859ps     994.2mV    1.161V     3.315V
1.108ns   2.523V     1.162V     3.434V
1.318ns   3.113V     1.253V     3.454V
1.499ns   3.235V     2.244V     3.461V
1.637ns   3.263V     2.623V     3.465V
2.283ns   3.295V     3.097V     3.469V
20ns      3.3V       3.14V      3.47V
[Falling Waveform]
R_fixture= 50.000
V_fixture= 3.300
V_fixture_min= 3.140
V_fixture_max= 3.470
|time   V(typ)   V(min)   V(max)
0s        3.3V       3.14V      3.47V
669ps     3.299V     3.14V      3.502V
1.152ns   3.313V     3.139V     1.087V
1.307ns   3.023V     3.14V      794.1mV
1.591ns   2.202V     3.219V     688.4mV
1.973ns   1.326V     3.107V     656.3mV
2.313ns   1.013V     2.708V     649.4mV
3.25ns    891.3mV    1.57V      646mV
4.356ns   879.4mV    1.217V     645.8mV
20ns      878.1mV    1.161V     645.8mV
[Falling Waveform]
R_fixture= 50.000
V_fixture= 0.0
V_fixture_min= 0.0
V_fixture_max= 0.0
|time   V(typ)   V(min)   V(max)
0s        2.349V     1.976V     2.802V
533ps     2.349V     1.976V     2.792V
634ps     2.349V     1.976V     1.772V
837ps     2.353V     1.976V     341.6mV
913ps     2.257V     1.976V     129.6mV
1.103ns   987.4mV    1.976V     34.87mV
1.48ns    94.11mV    1.935V     7.364mV
1.78ns    21.79mV    628.7mV    2.292mV
2.459ns   2.927mV    37.78mV    294.2uV
20ns      59.9nV     179nV      170.1nV
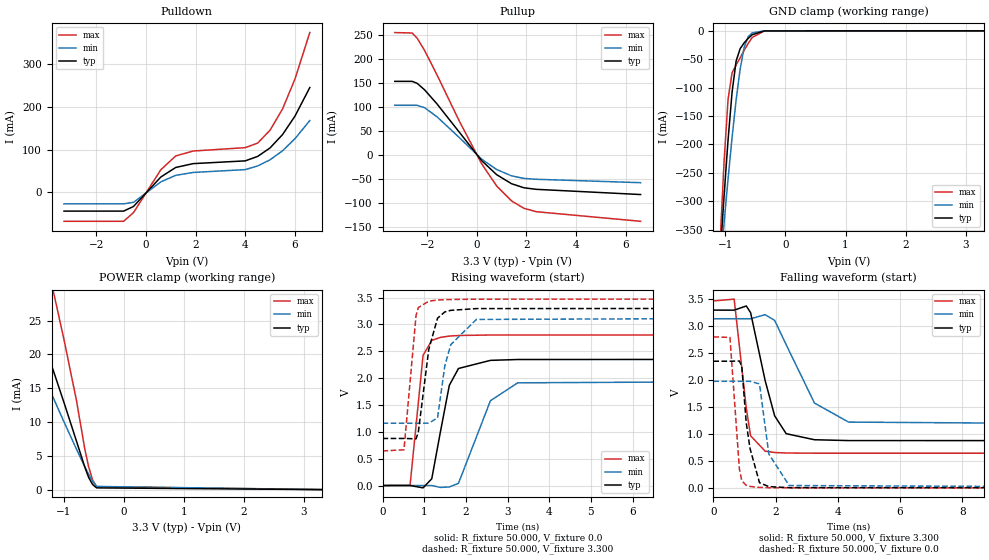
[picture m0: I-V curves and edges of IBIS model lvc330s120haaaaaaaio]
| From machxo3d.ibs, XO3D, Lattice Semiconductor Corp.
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|   Model lvc330s120haaaaaaaio
[Model] lvc330s120haaaaaaaio
Model_type I/O
Polarity   Non-Inverting
Enable   Active-Low
Vinl =  0.800V
Vinh =  2.000V
Vmeas =  1.650V
Cref =  0.0F
Rref =  1.000M
Vref =  0.0V
C_comp   4.200pF   3.800pF   7.500pF
[Temperature Range]   25.000   0.105k   -40.000
[Voltage Range]   3.300V   3.140V   3.470V
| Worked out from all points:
|   slope of the pulldown table from 0 to 0.495 V, typ, clamps not added: 16.2 ohm
|   slope of the pullup table from 0 to 0.495 V, typ, clamps not added: 17.8 ohm
|   GND clamp passes 1 mA (typ) near -0.43 V on its own axis
|   POWER clamp passes 1 mA (typ) near -0.53 V on its own axis
|   rising waveform, R_fixture 50.000, V_fixture 0.0: 20-80 % time 334ps typ, 560ps min, 179ps max; typ from 0 V to 2.35 V
|   rising waveform, R_fixture 50.000, V_fixture 3.300: 20-80 % time 293ps typ, 343ps min, 192ps max; typ from 0.876 V to 3.3 V
|   falling waveform, R_fixture 50.000, V_fixture 3.300: 20-80 % time 571ps typ, 996ps min, 313ps max; typ from 3.3 V to 0.876 V
|   falling waveform, R_fixture 50.000, V_fixture 0.0: 20-80 % time 305ps typ, 364ps min, 210ps max; typ from 2.35 V to 0 V
[Pulldown]
|Voltage   I(typ)   I(min)   I(max)
-3.3V     -43.98mA   -26.85mA   -67.81mA
-900mV    -43.98mA   -26.85mA   -67.81mA
-500mV    -33.06mA   -23.42mA   -47.39mA
600mV     35.86mA    24.47mA    52.84mA
1.2V      58.2mA     39.81mA    85.22mA
1.9V      67.18mA    46.53mA    96.69mA
4V        73.65mA    53.18mA    104.6mA
4.5V      84.05mA    61.72mA    115.2mA
5V        104mA      76.14mA    145.5mA
5.5V      135mA      97.17mA    194.9mA
6V        178.1mA    125.4mA    264.7mA
6.6V      245.3mA    168mA      374mA
[Pullup]
|Voltage   I(typ)   I(min)   I(max)
-3.3V     153.3mA    103.4mA    255.1mA
-2.6V     153.3mA    103.4mA    254.2mA
-2.4V     149.2mA    103.4mA    243.3mA
-2.1V     135.6mA    98.32mA    217.7mA
-1.6V     106.2mA    79.34mA    166.7mA
-700mV    47.13mA    35.94mA    70.14mA
200mV     -12.13mA   -9.077mA   -18.82mA
800mV     -41.29mA   -30.53mA   -64.86mA
1.4V      -60.2mA    -43.81mA   -96.07mA
1.9V      -68.67mA   -49.13mA   -111.5mA
2.4V      -71.91mA   -50.95mA   -118.6mA
6.6V      -82.78mA   -58.05mA   -138.6mA
[GND_clamp]
|Voltage   I(typ)   I(min)   I(max)
-3.3V     -4.507A    -3.482A    -6.263A
-1.089V   -398.4mA   -420.6mA   -374.7mA
-1.022V   -290.7mA   -338.6mA   -230.6mA
-955mV    -191.4mA   -260.2mA   -120.1mA
-888mV    -107.5mA   -187mA     -73.7mA
-821mV    -53mA      -121.4mA   -59.85mA
-754mV    -31.41mA   -66.94mA   -47.47mA
-687mV    -21.17mA   -28.82mA   -34.25mA
-620mV    -13.21mA   -10.23mA   -22mA
-553mV    -6.875mA   -3.578mA   -11.73mA
-352mV    -176.3uA   -89.98uA   -279uA
3.3V      50.87nA    0A         -26.43uA
[POWER_clamp]
|Voltage   I(typ)   I(min)   I(max)
-3.3V     62.1mA     51.02mA    92.7mA
-1.926V   36.35mA    28.59mA    56.55mA
-1.591V   28.28mA    21.98mA    45.01mA
-1.189V   18.03mA    13.9mA     29.96mA
-1.122V   16.26mA    12.55mA    27.31mA
-988mV    12.68mA    9.882mA    21.88mA
-787mV    7.154mA    5.963mA    13.15mA
-653mV    3.439mA    3.462mA    6.207mA
-586mV    1.819mA    2.29mA     3.395mA
-519mV    748.7uA    1.242mA    1.434mA
-452mV    255.4uA    468.1uA    442.9uA
3.3V      0A         0A         0A
[Ramp]
| variable   typ   min   max
dV/dt_r   1.410/0.333n   1.187/0.561n   1.682/0.178n
dV/dt_f   1.454/0.573n   1.188/0.989n   1.696/0.313n
R_load = 50.000
[Rising Waveform]
R_fixture= 50.000
V_fixture= 0.0
V_fixture_min= 0.0
V_fixture_max= 0.0
|time   V(typ)   V(min)   V(max)
0s        13.01nV    34.25nV    147.9nV
661ps     278.5uV    -5.394uV   4.618mV
973ps     -43.48mV   131.9uV    2.424V
1.182ns   126.2mV    -230.2uV   2.701V
1.386ns   985mV      -35.08mV   2.757V
1.603ns   1.865V     -27.17mV   2.782V
1.823ns   2.179V     40.85mV    2.793V
2.59ns    2.33V      1.579V     2.802V
3.245ns   2.346V     1.912V     2.803V
20ns      2.351V     1.978V     2.803V
[Rising Waveform]
R_fixture= 50.000
V_fixture= 3.300
V_fixture_min= 3.140
V_fixture_max= 3.470
|time   V(typ)   V(min)   V(max)
0s        876.5mV    1.16V      643.5mV
515ps     876.5mV    1.16V      665.6mV
804ps     868.9mV    1.16V      3.165V
859ps     992.1mV    1.16V      3.312V
1.11ns    2.535V     1.161V     3.432V
1.32ns    3.114V     1.259V     3.453V
1.495ns   3.232V     2.227V     3.46V
1.637ns   3.261V     2.622V     3.463V
2.252ns   3.294V     3.092V     3.469V
20ns      3.3V       3.14V      3.47V
[Falling Waveform]
R_fixture= 50.000
V_fixture= 3.300
V_fixture_min= 3.140
V_fixture_max= 3.470
|time   V(typ)   V(min)   V(max)
0s        3.3V       3.14V      3.47V
668ps     3.299V     3.14V      3.504V
1.058ns   3.377V     3.14V      1.479V
1.196ns   3.254V     3.14V      967.2mV
1.665ns   1.99V      3.215V     680.9mV
1.969ns   1.338V     3.11V      656.7mV
2.34ns    1.006V     2.658V     647mV
3.249ns   893.3mV    1.575V     643.7mV
4.345ns   878mV      1.221V     643.5mV
20ns      876.4mV    1.16V      643.5mV
[Falling Waveform]
R_fixture= 50.000
V_fixture= 0.0
V_fixture_min= 0.0
V_fixture_max= 0.0
|time   V(typ)   V(min)   V(max)
0s        2.351V     1.978V     2.803V
533ps     2.351V     1.978V     2.793V
837ps     2.355V     1.978V     348.8mV
914ps     2.254V     1.978V     132.2mV
1.055ns   1.215V     1.978V     47.23mV
1.179ns   729.7mV    1.978V     26.78mV
1.483ns   95.25mV    1.93V      8.184mV
1.782ns   23.5mV     628.7mV    2.623mV
2.438ns   4.018mV    43.14mV    327.4uV
20ns      54.05nV    172.7nV    159.3nV
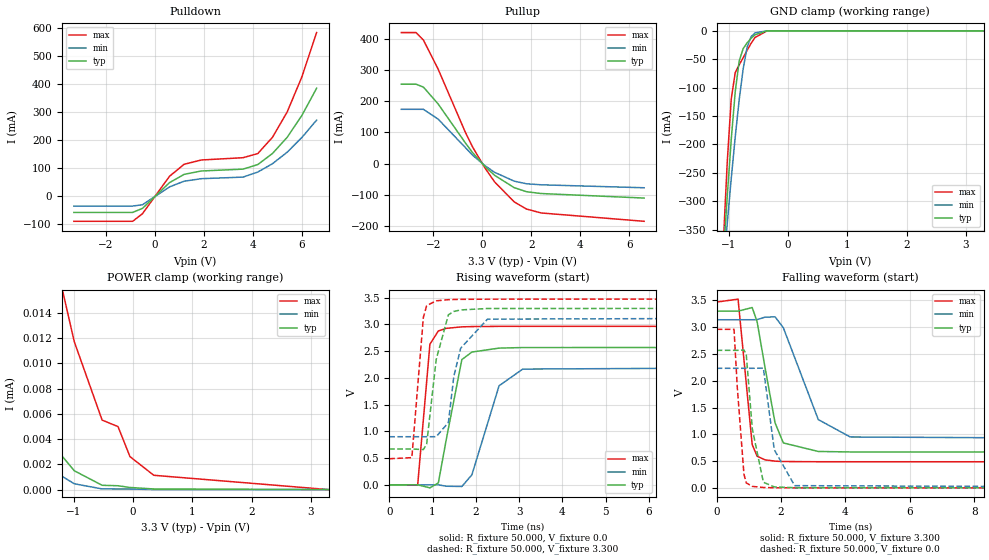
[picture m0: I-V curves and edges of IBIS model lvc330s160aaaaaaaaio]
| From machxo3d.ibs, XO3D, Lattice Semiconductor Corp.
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|   Model lvc330s160aaaaaaaaio
[Model] lvc330s160aaaaaaaaio
Model_type I/O
Polarity   Non-Inverting
Enable   Active-Low
Vinl =  0.800V
Vinh =  2.000V
Vmeas =  1.650V
Cref =  0.0F
Rref =  1.000M
Vref =  0.0V
C_comp   4.200pF   3.800pF   7.500pF
[Temperature Range]   25.000   0.105k   -40.000
[Voltage Range]   3.300V   3.140V   3.470V
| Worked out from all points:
|   slope of the pulldown table from 0 to 0.495 V, typ, clamps not added: 12.2 ohm
|   slope of the pullup table from 0 to 0.495 V, typ, clamps not added: 13.4 ohm
|   GND clamp passes 1 mA (typ) near -0.43 V on its own axis
|   rising waveform, R_fixture 50.000, V_fixture 0.0: 20-80 % time 283ps typ, 487ps min, 149ps max; typ from 0 V to 2.57 V
|   rising waveform, R_fixture 50.000, V_fixture 3.300: 20-80 % time 287ps typ, 343ps min, 181ps max; typ from 0.669 V to 3.3 V
|   falling waveform, R_fixture 50.000, V_fixture 3.300: 20-80 % time 463ps typ, 831ps min, 251ps max; typ from 3.3 V to 0.669 V
|   falling waveform, R_fixture 50.000, V_fixture 0.0: 20-80 % time 296ps typ, 360ps min, 198ps max; typ from 2.57 V to 0 V
[Pulldown]
|Voltage   I(typ)   I(min)   I(max)
-3.3V     -58.64mA   -35.81mA   -90.41mA
-900mV    -58.64mA   -35.81mA   -90.41mA
-500mV    -44.08mA   -31.23mA   -63.19mA
600mV     47.81mA    32.63mA    70.46mA
1.2V      77.59mA    53.08mA    113.6mA
1.9V      89.57mA    62.04mA    128.9mA
3.6V      96.17mA    67.68mA    137.1mA
4.2V      112.5mA    85.73mA    151.8mA
4.8V      152.1mA    115.6mA    210mA
5.4V      210mA      156.7mA    300.7mA
6V        288.3mA    209.5mA    426.4mA
6.6V      385.5mA    271.5mA    584.7mA
[Pullup]
|Voltage   I(typ)   I(min)   I(max)
-3.3V     254.2mA    173.8mA    419.5mA
-2.7V     254.2mA    173.8mA    419.5mA
-2.4V     244.9mA    173.8mA    395.6mA
-1.8V     191mA      142.4mA    302.6mA
-700mV    67.51mA    52.18mA    102mA
-400mV    35.48mA    27.29mA    53.85mA
100mV     -8.293mA   -6.216mA   -12.85mA
500mV     -37.38mA   -27.82mA   -58.35mA
1.3V      -76.97mA   -56.19mA   -122.5mA
1.8V      -89.97mA   -64.6mA    -145.5mA
2.4V      -95.88mA   -67.93mA   -158.1mA
6.6V      -110.4mA   -77.4mA    -184.8mA
[GND_clamp]
|Voltage   I(typ)   I(min)   I(max)
-3.3V     -4.507A    -3.482A    -6.263A
-1.089V   -398.4mA   -420.6mA   -374.7mA
-1.022V   -290.7mA   -338.6mA   -230.6mA
-955mV    -191.3mA   -260.2mA   -120mA
-888mV    -107.5mA   -187mA     -73.64mA
-821mV    -52.96mA   -121.4mA   -59.79mA
-754mV    -31.36mA   -66.92mA   -47.4mA
-687mV    -21.12mA   -28.79mA   -34.18mA
-620mV    -13.16mA   -10.19mA   -21.93mA
-553mV    -6.814mA   -3.53mA    -11.64mA
-352mV    -96.36uA   -46.21uA   -149.8uA
3.3V      0A         0A         0A
[POWER_clamp]
|Voltage   I(typ)   I(min)   I(max)
-3.3V     732.2uA    455.9uA    1.265mA
-2.663V   69.44uA    15.46uA    306.8uA
-2.529V   27.69uA    10.95uA    164.1uA
-2.328V   15.69uA    8.498uA    64.68uA
-1.725V   7.348uA    3.693uA    30.69uA
-1.189V   2.632uA    1.04uA     15.85uA
-988mV    1.494uA    463.1nA    11.72uA
-519mV    342.8nA    54.79nA    5.51uA
-251mV    305.1nA    47.66nA    4.994uA
-50mV     169nA      47.66nA    2.616uA
352mV     50.67nA    4.149nA    1.135uA
3.3V      0A         0A         0A
[Ramp]
| variable   typ   min   max
dV/dt_r   1.541/0.281n   1.340/0.484n   1.777/0.149n
dV/dt_f   1.578/0.464n   1.345/0.828n   1.789/0.251n
R_load = 50.000
[Rising Waveform]
R_fixture= 50.000
V_fixture= 0.0
V_fixture_min= 0.0
V_fixture_max= 0.0
|time   V(typ)   V(min)   V(max)
0s        10.54nV    27.99nV    119.6nV
657ps     228.9uV    14.68uV    -7.34mV
940ps     -56.33mV   38.68uV    2.627V
1.135ns   36.8mV     160.3uV    2.876V
1.32ns    857.3mV    -25.75mV   2.924V
1.677ns   2.34V      -30.81mV   2.952V
1.909ns   2.481V     187mV      2.957V
2.537ns   2.555V     1.851V     2.961V
3.083ns   2.565V     2.163V     2.961V
20ns      2.568V     2.233V     2.961V
[Rising Waveform]
R_fixture= 50.000
V_fixture= 3.300
V_fixture_min= 3.140
V_fixture_max= 3.470
|time   V(typ)   V(min)   V(max)
0s        669.4mV    899.2mV    487.7mV
523ps     669.4mV    899.2mV    508.1mV
789ps     659.1mV    899.2mV    3.13V
865ps     761.5mV    899.2mV    3.349V
1.085ns   2.343V     899.5mV    3.438V
1.367ns   3.177V     1.165V     3.46V
1.492ns   3.24V      2.025V     3.463V
1.65ns    3.268V     2.553V     3.466V
2.27ns    3.295V     3.096V     3.469V
20ns      3.3V       3.14V      3.47V
[Falling Waveform]
R_fixture= 50.000
V_fixture= 3.300
V_fixture_min= 3.140
V_fixture_max= 3.470
|time   V(typ)   V(min)   V(max)
0s        3.3V       3.14V      3.47V
664ps     3.3V       3.14V      3.525V
1.103ns   3.368V     3.14V      808.8mV
1.255ns   3.106V     3.142V     592.3mV
1.501ns   2.252V     3.188V     523.2mV
1.814ns   1.214V     3.194V     498.8mV
2.071ns   839.2mV    2.991V     491.9mV
3.157ns   679.7mV    1.275V     487.8mV
4.15ns    670.7mV    950.5mV    487.6mV
20ns      669.4mV    899.2mV    487.6mV
[Falling Waveform]
R_fixture= 50.000
V_fixture= 0.0
V_fixture_min= 0.0
V_fixture_max= 0.0
|time   V(typ)   V(min)   V(max)
0s        2.568V     2.233V     2.961V
539ps     2.568V     2.233V     2.961V
640ps     2.568V     2.233V     1.875V
847ps     2.575V     2.233V     254.1mV
919ps     2.488V     2.233V     92.75mV
1.107ns   1.101V     2.233V     27.5mV
1.451ns   104.6mV    2.236V     6.916mV
1.79ns    18.04mV    711.7mV    2.054mV
2.423ns   2.881mV    41.58mV    237.1uV
20ns      47.49nV    150nV      132.7nV
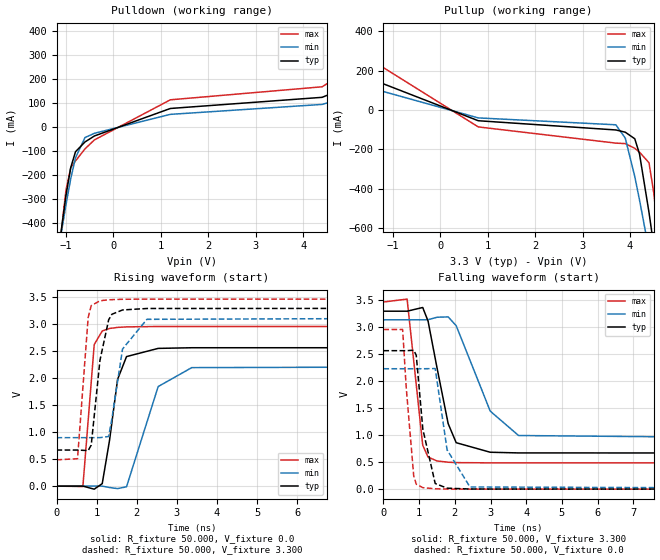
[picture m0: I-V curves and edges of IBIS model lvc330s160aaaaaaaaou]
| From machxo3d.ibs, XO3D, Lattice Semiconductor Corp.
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|   Model lvc330s160aaaaaaaaou
[Model] lvc330s160aaaaaaaaou
Model_type Output
Polarity   Non-Inverting
Enable   Active-High
Vmeas =  1.650V
Cref =  0.0F
Rref =  1.000M
Vref =  0.0V
C_comp   4.200pF   3.800pF   7.500pF
[Temperature Range]   25.000   0.105k   -40.000
[Voltage Range]   3.300V   3.140V   3.470V
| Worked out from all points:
|   slope of the pulldown table from 0 to 0.495 V, typ, clamps not added: 12.2 ohm
|   slope of the pullup table from 0 to 0.495 V, typ, clamps not added: 13.4 ohm
|   rising waveform, R_fixture 50.000, V_fixture 0.0: 20-80 % time 284ps typ, 487ps min, 150ps max; typ from 0 V to 2.57 V
|   rising waveform, R_fixture 50.000, V_fixture 3.300: 20-80 % time 287ps typ, 343ps min, 181ps max; typ from 0.669 V to 3.3 V
|   falling waveform, R_fixture 50.000, V_fixture 3.300: 20-80 % time 463ps typ, 830ps min, 251ps max; typ from 3.3 V to 0.669 V
|   falling waveform, R_fixture 50.000, V_fixture 0.0: 20-80 % time 298ps typ, 362ps min, 198ps max; typ from 2.57 V to 0 V
[Pulldown]
|Voltage   I(typ)   I(min)   I(max)
-3.3V     -4.508A    -3.483A    -6.264A
-1.1V     -430mA     -440.6mA   -433.4mA
-1V       -282.5mA   -321.4mA   -261.3mA
-900mV    -168mA     -213.9mA   -168.3mA
-800mV    -102.2mA   -127.5mA   -140.6mA
-600mV    -61.55mA   -43.25mA   -90.15mA
-400mV    -36.57mA   -25.48mA   -52.9mA
1.2V      77.59mA    53.08mA    113.6mA
4.4V      123.9mA    94.45mA    167.7mA
5.2V      188.5mA    141.7mA    266.7mA
6V        288.4mA    209.6mA    426.6mA
6.6V      386.2mA    272.1mA    585.7mA
[Pullup]
|Voltage   I(typ)   I(min)   I(max)
-3.3V     254.3mA    173.8mA    419.8mA
-2.4V     244.9mA    173.8mA    395.6mA
800mV     -55.05mA   -40.71mA   -86.48mA
3.7V      -101.9mA   -75.64mA   -168.8mA
3.9V      -113.4mA   -143.5mA   -171.4mA
4.1V      -146.7mA   -338.6mA   -195.1mA
4.2V      -224.3mA   -457.7mA   -214.8mA
4.4V      -521mA     -713.3mA   -268.6mA
4.5V      -691.6mA   -845.9mA   -420.8mA
4.6V      -867.9mA   -980.3mA   -645.1mA
4.7V      -1.048A    -1.116A    -890.7mA
6.6V      -4.617A    -3.787A    -5.985A
[Ramp]
| variable   typ   min   max
dV/dt_r   1.541/0.281n   1.340/0.484n   1.777/0.149n
dV/dt_f   1.578/0.464n   1.345/0.828n   1.789/0.251n
R_load = 50.000
[Rising Waveform]
R_fixture= 50.000
V_fixture= 0.0
V_fixture_min= 0.0
V_fixture_max= 0.0
|time   V(typ)   V(min)   V(max)
0s        10.54nV    27.99nV    119.6nV
657ps     212.7uV    13.91uV    -7.345mV
940ps     -56.34mV   38.87uV    2.627V
1.14ns    46.99mV    154.2uV    2.878V
1.323ns   857.3mV    -25.75mV   2.925V
1.522ns   1.98V      -45.43mV   2.944V
1.745ns   2.403V     -12.57mV   2.954V
2.534ns   2.555V     1.847V     2.961V
3.37ns    2.567V     2.198V     2.961V
20ns      2.568V     2.233V     2.961V
[Rising Waveform]
R_fixture= 50.000
V_fixture= 3.300
V_fixture_min= 3.140
V_fixture_max= 3.470
|time   V(typ)   V(min)   V(max)
0s        669.4mV    899.2mV    487.7mV
523ps     669.4mV    899.2mV    508.1mV
789ps     659.1mV    899.2mV    3.13V
865ps     761.5mV    899.2mV    3.349V
1.083ns   2.335V     899.5mV    3.438V
1.3ns     3.086V     921.1mV    3.457V
1.38ns    3.188V     1.25V      3.459V
1.646ns   3.268V     2.544V     3.466V
2.253ns   3.295V     3.094V     3.469V
20ns      3.3V       3.14V      3.47V
[Falling Waveform]
R_fixture= 50.000
V_fixture= 3.300
V_fixture_min= 3.140
V_fixture_max= 3.470
|time   V(typ)   V(min)   V(max)
0s        3.3V       3.14V      3.47V
664ps     3.3V       3.14V      3.525V
1.101ns   3.369V     3.14V      815.3mV
1.251ns   3.116V     3.142V     594.5mV
1.501ns   2.252V     3.188V     523.4mV
1.814ns   1.214V     3.194V     499.6mV
2.039ns   861.6mV    3.031V     492.6mV
2.992ns   684.6mV    1.447V     487.8mV
3.786ns   672.1mV    994.8mV    487.7mV
20ns      669.4mV    899.1mV    487.6mV
[Falling Waveform]
R_fixture= 50.000
V_fixture= 0.0
V_fixture_min= 0.0
V_fixture_max= 0.0
|time   V(typ)   V(min)   V(max)
0s        2.568V     2.233V     2.961V
539ps     2.568V     2.233V     2.961V
640ps     2.568V     2.233V     1.875V
849ps     2.576V     2.233V     245.9mV
920ps     2.484V     2.233V     91.73mV
1.105ns   1.11V      2.233V     27.67mV
1.451ns   104.6mV    2.236V     6.814mV
1.784ns   18.51mV    727.6mV    2.021mV
2.425ns   2.96mV     40.74mV    233.6uV
20ns      48.37nV    149.8nV    132.6nV
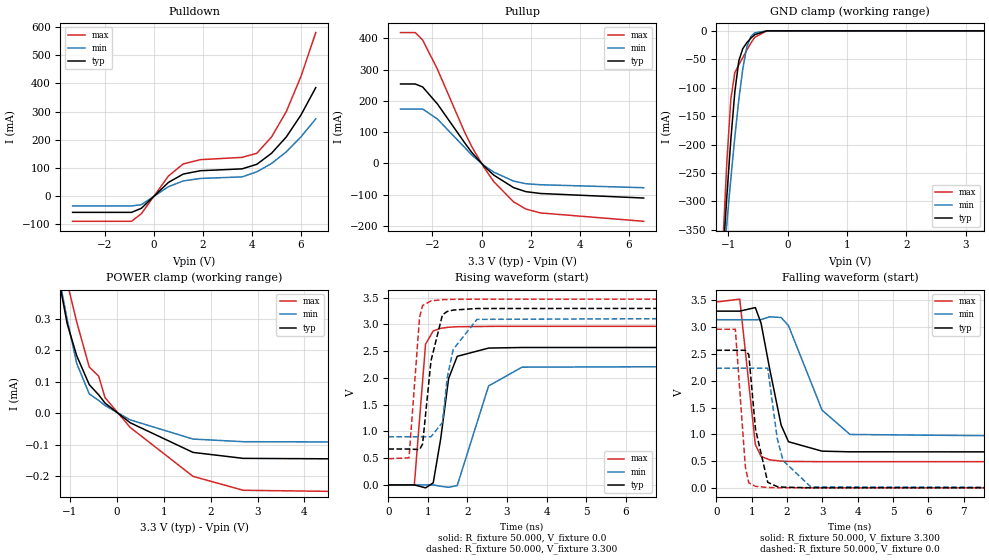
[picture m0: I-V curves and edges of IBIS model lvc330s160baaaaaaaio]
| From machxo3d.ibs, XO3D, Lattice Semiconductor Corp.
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|   Model lvc330s160baaaaaaaio
[Model] lvc330s160baaaaaaaio
Model_type I/O
Polarity   Non-Inverting
Enable   Active-Low
Vinl =  0.800V
Vinh =  2.000V
Vmeas =  1.650V
Cref =  0.0F
Rref =  1.000M
Vref =  0.0V
C_comp   4.200pF   3.800pF   7.500pF
[Temperature Range]   25.000   0.105k   -40.000
[Voltage Range]   3.300V   3.140V   3.470V
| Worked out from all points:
|   slope of the pulldown table from 0 to 0.495 V, typ, clamps not added: 12.2 ohm
|   slope of the pullup table from 0 to 0.495 V, typ, clamps not added: 13.4 ohm
|   GND clamp passes 1 mA (typ) near -0.43 V on its own axis
|   POWER clamp passes 1 mA (typ) near -1.85 V on its own axis
|   rising waveform, R_fixture 50.000, V_fixture 0.0: 20-80 % time 283ps typ, 487ps min, 150ps max; typ from 0.001 V to 2.57 V
|   rising waveform, R_fixture 50.000, V_fixture 3.300: 20-80 % time 292ps typ, 344ps min, 180ps max; typ from 0.671 V to 3.3 V
|   falling waveform, R_fixture 50.000, V_fixture 3.300: 20-80 % time 465ps typ, 831ps min, 252ps max; typ from 3.3 V to 0.671 V
|   falling waveform, R_fixture 50.000, V_fixture 0.0: 20-80 % time 298ps typ, 362ps min, 198ps max; typ from 2.57 V to 0.001 V
[Pulldown]
|Voltage   I(typ)   I(min)   I(max)
-3.3V     -58.64mA   -35.81mA   -90.41mA
-900mV    -58.64mA   -35.81mA   -90.41mA
-500mV    -44.08mA   -31.23mA   -63.19mA
600mV     47.81mA    32.63mA    70.46mA
1.2V      77.59mA    53.08mA    113.6mA
1.9V      89.57mA    62.04mA    128.9mA
3.6V      96.17mA    67.67mA    137.1mA
4.2V      112.4mA    85.6mA     151.6mA
4.8V      151.7mA    115.4mA    209.7mA
5.4V      209.6mA    156.8mA    299.9mA
6V        288.2mA    210.3mA    425.6mA
6.6V      385.3mA    274.1mA    581.2mA
[Pullup]
|Voltage   I(typ)   I(min)   I(max)
-3.3V     254.2mA    174.2mA    418.6mA
-2.7V     254.2mA    174.2mA    418.6mA
-2.4V     244.7mA    174.2mA    394.8mA
-1.8V     190.6mA    142.3mA    301.9mA
-700mV    67.45mA    52.16mA    101.9mA
-400mV    35.48mA    27.29mA    53.85mA
100mV     -8.293mA   -6.216mA   -12.85mA
500mV     -37.38mA   -27.82mA   -58.35mA
1.3V      -76.97mA   -56.19mA   -122.5mA
1.8V      -89.97mA   -64.6mA    -145.5mA
2.4V      -95.88mA   -67.93mA   -158.1mA
6.6V      -110.4mA   -77.4mA    -184.8mA
[GND_clamp]
|Voltage   I(typ)   I(min)   I(max)
-3.3V     -4.506A    -3.482A    -6.262A
-1.089V   -398.3mA   -420.5mA   -374.5mA
-1.022V   -290.6mA   -338.5mA   -230.4mA
-955mV    -191.2mA   -260.1mA   -119.8mA
-888mV    -107.4mA   -186.9mA   -73.47mA
-821mV    -52.87mA   -121.3mA   -59.62mA
-754mV    -31.28mA   -66.86mA   -47.24mA
-687mV    -21.04mA   -28.74mA   -34.02mA
-620mV    -13.09mA   -10.15mA   -21.79mA
-553mV    -6.755mA   -3.505mA   -11.52mA
-352mV    -90.18uA   -45.39uA   -119.9uA
3.3V      0A         0A         0A
[POWER_clamp]
|Voltage   I(typ)   I(min)   I(max)
-3.3V     3.967mA    2.512mA    11.53mA
-1.323V   507.3uA    506.4uA    605.6uA
-1.189V   387.7uA    399.8uA    501.1uA
-1.055V   282.8uA    296.7uA    413.8uA
-854mV    182.6uA    158.2uA    289.7uA
-586mV    90.73uA    61.33uA    146.6uA
-385mV    58.36uA    40.66uA    117.5uA
-251mV    32.53uA    24.74uA    49.87uA
285mV     -29.95uA   -20.85uA   -44.72uA
1.625V    -124uA     -81.72uA   -199.9uA
2.697V    -142.9uA   -90.03uA   -244.1uA
6.6V      -145.9uA   -91.75uA   -251.2uA
[Ramp]
| variable   typ   min   max
dV/dt_r   1.541/0.281n   1.340/0.484n   1.776/0.149n
dV/dt_f   1.577/0.465n   1.344/0.830n   1.788/0.252n
R_load = 50.000
[Rising Waveform]
R_fixture= 50.000
V_fixture= 0.0
V_fixture_min= 0.0
V_fixture_max= 0.0
|time   V(typ)   V(min)   V(max)
0s        1.249mV    1.066mV    1.539mV
656ps     1.468mV    1.077mV    -4.124mV
940ps     -53.89mV   1.102mV    2.629V
1.134ns   39.75mV    871.4uV    2.876V
1.322ns   856.7mV    -23.9mV    2.925V
1.523ns   1.988V     -43.56mV   2.945V
1.741ns   2.402V     -10.41mV   2.954V
2.534ns   2.556V     1.849V     2.961V
3.381ns   2.567V     2.2V       2.962V
20ns      2.569V     2.234V     2.962V
[Rising Waveform]
R_fixture= 50.000
V_fixture= 3.300
V_fixture_min= 3.140
V_fixture_max= 3.470
|time   V(typ)   V(min)   V(max)
0s        671.1mV    900.8mV    489.6mV
522ps     671.1mV    900.8mV    507.1mV
789ps     660.8mV    900.8mV    3.132V
865ps     763.8mV    900.8mV    3.35V
1.078ns   2.32V      901.2mV    3.437V
1.367ns   3.177V     1.167V     3.46V
1.487ns   3.239V     2.001V     3.463V
1.64ns    3.266V     2.533V     3.466V
2.241ns   3.295V     3.092V     3.469V
20ns      3.3V       3.14V      3.47V
[Falling Waveform]
R_fixture= 50.000
V_fixture= 3.300
V_fixture_min= 3.140
V_fixture_max= 3.470
|time   V(typ)   V(min)   V(max)
0s        3.3V       3.14V      3.47V
664ps     3.3V       3.14V      3.524V
1.104ns   3.366V     3.14V      811.1mV
1.266ns   3.075V     3.141V     589.2mV
1.507ns   2.232V     3.194V     524.6mV
1.834ns   1.171V     3.181V     499.9mV
2.043ns   861.8mV    3.027V     494.5mV
2.991ns   686.3mV    1.452V     489.8mV
3.782ns   673.8mV    997.6mV    489.5mV
20ns      671.1mV    900.8mV    489.5mV
[Falling Waveform]
R_fixture= 50.000
V_fixture= 0.0
V_fixture_min= 0.0
V_fixture_max= 0.0
|time   V(typ)   V(min)   V(max)
0s        2.569V     2.234V     2.962V
539ps     2.569V     2.234V     2.961V
823ps     2.569V     2.234V     384.9mV
919ps     2.49V      2.234V     95.69mV
1.109ns   1.097V     2.234V     29.06mV
1.455ns   104.1mV    2.235V     8.026mV
1.724ns   24.85mV    920.3mV    3.959mV
1.89ns    14.39mV    508.8mV    3.027mV
2.674ns   2.778mV    18.54mV    1.694mV
20ns      1.249mV    1.066mV    1.539mV
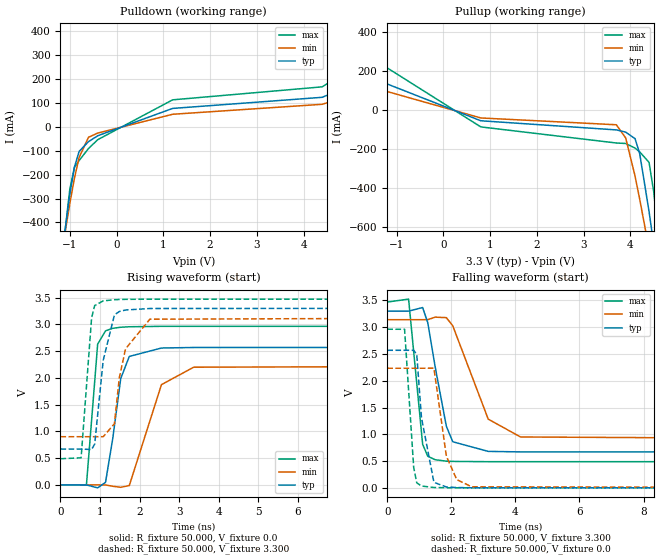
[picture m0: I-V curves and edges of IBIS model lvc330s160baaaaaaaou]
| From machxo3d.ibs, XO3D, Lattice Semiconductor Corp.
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|   Model lvc330s160baaaaaaaou
[Model] lvc330s160baaaaaaaou
Model_type Output
Polarity   Non-Inverting
Enable   Active-High
Vmeas =  1.650V
Cref =  0.0F
Rref =  1.000M
Vref =  0.0V
C_comp   4.200pF   3.800pF   7.500pF
[Temperature Range]   25.000   0.105k   -40.000
[Voltage Range]   3.300V   3.140V   3.470V
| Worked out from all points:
|   slope of the pulldown table from 0 to 0.495 V, typ, clamps not added: 12.2 ohm
|   slope of the pullup table from 0 to 0.495 V, typ, clamps not added: 13.3 ohm
|   rising waveform, R_fixture 50.000, V_fixture 0.0: 20-80 % time 283ps typ, 487ps min, 150ps max; typ from 0.001 V to 2.57 V
|   rising waveform, R_fixture 50.000, V_fixture 3.300: 20-80 % time 292ps typ, 344ps min, 181ps max; typ from 0.671 V to 3.3 V
|   falling waveform, R_fixture 50.000, V_fixture 3.300: 20-80 % time 465ps typ, 832ps min, 252ps max; typ from 3.3 V to 0.671 V
|   falling waveform, R_fixture 50.000, V_fixture 0.0: 20-80 % time 298ps typ, 362ps min, 198ps max; typ from 2.57 V to 0.001 V
[Pulldown]
|Voltage   I(typ)   I(min)   I(max)
-3.3V     -4.508A    -3.483A    -6.264A
-1.1V     -430.1mA   -440.6mA   -433.4mA
-1V       -282.5mA   -321.4mA   -261.4mA
-900mV    -168.1mA   -213.9mA   -168.3mA
-800mV    -102.3mA   -127.5mA   -140.7mA
-600mV    -61.63mA   -43.3mA    -90.26mA
-400mV    -36.69mA   -25.57mA   -53.1mA
1.2V      77.46mA    52.99mA    113.4mA
4.4V      124mA      94.74mA    167.8mA
5.2V      189.1mA    142.8mA    267mA
6V        290.1mA    212.3mA    427.9mA
6.6V      389.2mA    276.9mA    588.3mA
[Pullup]
|Voltage   I(typ)   I(min)   I(max)
-3.3V     255.9mA    175.6mA    421.5mA
-2.4V     246.2mA    175.6mA    396.7mA
800mV     -55.13mA   -40.76mA   -86.59mA
3.7V      -102mA     -75.7mA    -169.1mA
3.9V      -113.4mA   -143.5mA   -171.6mA
4.1V      -146.7mA   -338.7mA   -195.2mA
4.2V      -224.4mA   -457.7mA   -214.8mA
4.4V      -521mA     -713.3mA   -268.6mA
4.5V      -691.6mA   -845.9mA   -420.8mA
4.6V      -867.9mA   -980.3mA   -645.1mA
4.7V      -1.048A    -1.116A    -890.8mA
6.6V      -4.617A    -3.787A    -5.985A
[Ramp]
| variable   typ   min   max
dV/dt_r   1.541/0.281n   1.340/0.484n   1.776/0.149n
dV/dt_f   1.577/0.465n   1.344/0.830n   1.788/0.252n
R_load = 50.000
[Rising Waveform]
R_fixture= 50.000
V_fixture= 0.0
V_fixture_min= 0.0
V_fixture_max= 0.0
|time   V(typ)   V(min)   V(max)
0s        1.249mV    1.066mV    1.539mV
656ps     1.467mV    1.079mV    -4.129mV
940ps     -53.9mV    1.103mV    2.629V
1.139ns   49.84mV    841.5uV    2.878V
1.319ns   856.8mV    -23.89mV   2.925V
1.523ns   1.988V     -43.57mV   2.945V
1.739ns   2.4V       -11.33mV   2.954V
2.551ns   2.557V     1.873V     2.962V
3.365ns   2.567V     2.199V     2.962V
20ns      2.569V     2.234V     2.962V
[Rising Waveform]
R_fixture= 50.000
V_fixture= 3.300
V_fixture_min= 3.140
V_fixture_max= 3.470
|time   V(typ)   V(min)   V(max)
0s        671.1mV    900.8mV    489.6mV
522ps     671.2mV    900.8mV    507.1mV
787ps     661.2mV    900.8mV    3.12V
865ps     763.8mV    900.8mV    3.35V
1.08ns    2.327V     901.2mV    3.437V
1.363ns   3.174V     1.143V     3.459V
1.487ns   3.239V     2.001V     3.463V
1.644ns   3.267V     2.542V     3.466V
2.259ns   3.295V     3.095V     3.469V
20ns      3.3V       3.14V      3.47V
[Falling Waveform]
R_fixture= 50.000
V_fixture= 3.300
V_fixture_min= 3.140
V_fixture_max= 3.470
|time   V(typ)   V(min)   V(max)
0s        3.3V       3.14V      3.47V
664ps     3.3V       3.14V      3.524V
1.103ns   3.367V     3.14V      814.4mV
1.263ns   3.083V     3.141V     590.7mV
1.495ns   2.258V     3.188V     526.4mV
1.843ns   1.151V     3.178V     499.4mV
2.043ns   861.8mV    3.027V     494.6mV
3.151ns   681.8mV    1.284V     489.7mV
4.16ns    672.4mV    951mV      489.6mV
20ns      671.1mV    900.8mV    489.6mV
[Falling Waveform]
R_fixture= 50.000
V_fixture= 0.0
V_fixture_min= 0.0
V_fixture_max= 0.0
|time   V(typ)   V(min)   V(max)
0s        2.569V     2.234V     2.962V
539ps     2.569V     2.234V     2.961V
823ps     2.569V     2.234V     384.8mV
919ps     2.49V      2.234V     95.67mV
1.066ns   1.314V     2.234V     35.27mV
1.455ns   104.1mV    2.235V     8.112mV
1.844ns   17.35mV    592.8mV    3.139mV
2.168ns   7.306mV    155mV      2.081mV
2.636ns   2.919mV    20.68mV    1.661mV
20ns      1.249mV    1.066mV    1.539mV
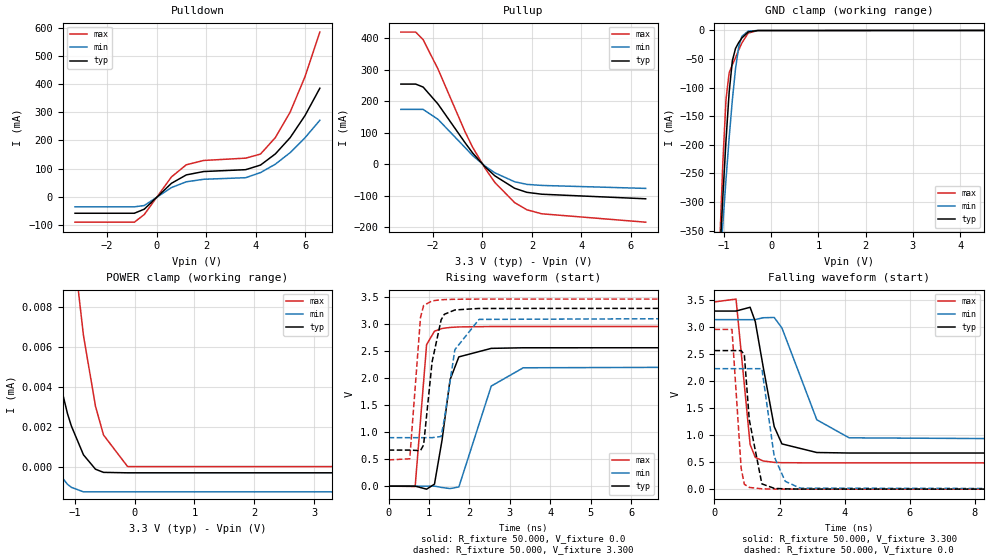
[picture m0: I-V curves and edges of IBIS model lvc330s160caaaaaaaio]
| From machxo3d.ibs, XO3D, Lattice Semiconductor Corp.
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|   Model lvc330s160caaaaaaaio
[Model] lvc330s160caaaaaaaio
Model_type I/O
Polarity   Non-Inverting
Enable   Active-Low
Vinl =  0.800V
Vinh =  2.000V
Vmeas =  1.650V
Cref =  0.0F
Rref =  1.000M
Vref =  0.0V
C_comp   4.200pF   3.800pF   7.500pF
[Temperature Range]   25.000   0.105k   -40.000
[Voltage Range]   3.300V   3.140V   3.470V
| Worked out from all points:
|   slope of the pulldown table from 0 to 0.495 V, typ, clamps not added: 12.2 ohm
|   slope of the pullup table from 0 to 0.495 V, typ, clamps not added: 13.4 ohm
|   GND clamp passes 1 mA (typ) near -0.43 V on its own axis
|   rising waveform, R_fixture 50.000, V_fixture 0.0: 20-80 % time 283ps typ, 487ps min, 150ps max; typ from 0 V to 2.57 V
|   rising waveform, R_fixture 50.000, V_fixture 3.300: 20-80 % time 292ps typ, 348ps min, 181ps max; typ from 0.668 V to 3.3 V
|   falling waveform, R_fixture 50.000, V_fixture 3.300: 20-80 % time 463ps typ, 829ps min, 251ps max; typ from 3.3 V to 0.668 V
|   falling waveform, R_fixture 50.000, V_fixture 0.0: 20-80 % time 298ps typ, 359ps min, 197ps max; typ from 2.57 V to 0 V
[Pulldown]
|Voltage   I(typ)   I(min)   I(max)
-3.3V     -58.64mA   -35.81mA   -90.41mA
-900mV    -58.64mA   -35.81mA   -90.41mA
-500mV    -44.08mA   -31.23mA   -63.19mA
600mV     47.81mA    32.63mA    70.46mA
1.2V      77.59mA    53.08mA    113.6mA
1.9V      89.57mA    62.04mA    128.9mA
3.6V      96.17mA    67.67mA    137.1mA
4.2V      112.5mA    85.73mA    151.6mA
4.8V      152.1mA    115.6mA    210mA
5.4V      210mA      156.7mA    300.7mA
6V        288.4mA    209.5mA    426.5mA
6.6V      385.6mA    271.6mA    585mA
[Pullup]
|Voltage   I(typ)   I(min)   I(max)
-3.3V     254.3mA    173.8mA    419.6mA
-2.7V     254.3mA    173.8mA    419.6mA
-2.4V     244.9mA    173.8mA    395.6mA
-1.8V     191mA      142.4mA    302.5mA
-700mV    67.48mA    52.18mA    101.9mA
-400mV    35.48mA    27.29mA    53.84mA
100mV     -8.293mA   -6.216mA   -12.85mA
500mV     -37.38mA   -27.82mA   -58.35mA
1.3V      -76.97mA   -56.19mA   -122.5mA
1.8V      -89.97mA   -64.6mA    -145.5mA
2.4V      -95.88mA   -67.93mA   -158.1mA
6.6V      -110.4mA   -77.4mA    -184.8mA
[GND_clamp]
|Voltage   I(typ)   I(min)   I(max)
-3.3V     -4.507A    -3.482A    -6.263A
-1.089V   -398.4mA   -420.6mA   -374.7mA
-1.022V   -290.7mA   -338.6mA   -230.6mA
-955mV    -191.4mA   -260.2mA   -120.1mA
-888mV    -107.5mA   -187mA     -73.7mA
-821mV    -53mA      -121.4mA   -59.85mA
-754mV    -31.41mA   -66.94mA   -47.47mA
-687mV    -21.17mA   -28.82mA   -34.25mA
-620mV    -13.21mA   -10.23mA   -22mA
-486mV    -2.63mA    -1.112mA   -4.479mA
-285mV    -80.91uA   -42.41uA   -152.3uA
6.6V      121.2uA    55.82uA    291.2uA
[POWER_clamp]
|Voltage   I(typ)   I(min)   I(max)
-3.3V     704.7uA    440.9uA    1.167mA
-2.596V   46.79uA    12.42uA    184.2uA
-2.328V   25.67uA    8.107uA    76.87uA
-1.792V   13.09uA    2.762uA    43.68uA
-1.39V    5.98uA     124.1nA    24.26uA
-1.122V   2.656uA    -886.1nA   13.98uA
-1.055V   2.02uA     -1.042uA   11.85uA
-854mV    585.7nA    -1.267uA   6.557uA
-653mV    -133.8nA   -1.267uA   3.017uA
-519mV    -290.6nA   -1.267uA   1.58uA
-117mV    -313.6nA   -1.267uA   0A
3.3V      -313.6nA   -1.267uA   0A
[Ramp]
| variable   typ   min   max
dV/dt_r   1.540/0.281n   1.339/0.484n   1.776/0.149n
dV/dt_f   1.578/0.464n   1.345/0.828n   1.789/0.251n
R_load = 50.000
[Rising Waveform]
R_fixture= 50.000
V_fixture= 0.0
V_fixture_min= 0.0
V_fixture_max= 0.0
|time   V(typ)   V(min)   V(max)
0s        10.33nV    27.72nV    115.7nV
657ps     227.8uV    14.64uV    -6.898mV
940ps     -56.24mV   38.65uV    2.624V
1.135ns   37.1mV     159.3uV    2.873V
1.323ns   856.6mV    -25.75mV   2.923V
1.521ns   1.974V     -45.21mV   2.942V
1.738ns   2.396V     -15.21mV   2.951V
2.54ns    2.554V     1.855V     2.959V
3.332ns   2.565V     2.194V     2.959V
20ns      2.567V     2.232V     2.959V
[Rising Waveform]
R_fixture= 50.000
V_fixture= 3.300
V_fixture_min= 3.140
V_fixture_max= 3.470
|time   V(typ)   V(min)   V(max)
0s        668.3mV    898.5mV    486.2mV
523ps     668.3mV    898.5mV    506.4mV
789ps     658mV      898.5mV    3.125V
866ps     765mV      898.5mV    3.348V
1.076ns   2.304V     898.9mV    3.435V
1.3ns     3.084V     920.4mV    3.455V
1.38ns    3.186V     1.249V     3.458V
1.64ns    3.266V     2.53V      3.464V
2.238ns   3.294V     3.091V     3.468V
20ns      3.299V     3.14V      3.468V
[Falling Waveform]
R_fixture= 50.000
V_fixture= 3.300
V_fixture_min= 3.140
V_fixture_max= 3.470
|time   V(typ)   V(min)   V(max)
0s        3.299V     3.14V      3.468V
663ps     3.299V     3.14V      3.521V
1.096ns   3.369V     3.139V     826.4mV
1.254ns   3.104V     3.141V     590.4mV
1.493ns   2.278V     3.175V     523mV
1.835ns   1.16V      3.18V      496.2mV
2.072ns   838.5mV    2.988V     490.5mV
3.144ns   678.9mV    1.285V     486.4mV
4.136ns   669.6mV    950.9mV    486.2mV
20ns      668.3mV    898.5mV    486.2mV
[Falling Waveform]
R_fixture= 50.000
V_fixture= 0.0
V_fixture_min= 0.0
V_fixture_max= 0.0
|time   V(typ)   V(min)   V(max)
0s        2.567V     2.232V     2.959V
539ps     2.567V     2.232V     2.958V
820ps     2.567V     2.232V     390.1mV
918ps     2.491V     2.232V     91.57mV
1.069ns   1.29V      2.232V     32.45mV
1.457ns   98.14mV    2.232V     6.317mV
1.837ns   15.19mV    600.7mV    1.729mV
2.174ns   5.532mV    145.6mV    466.4uV
2.63ns    1.668mV    19.39mV    153.7uV
20ns      43.42nV    146.7nV    125.2nV
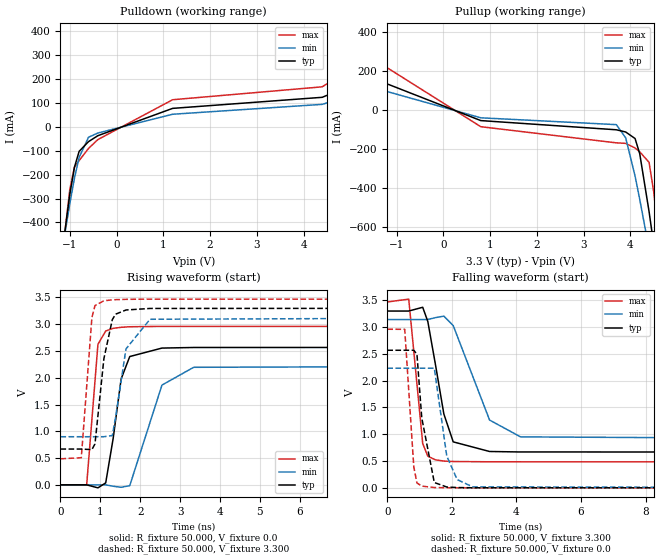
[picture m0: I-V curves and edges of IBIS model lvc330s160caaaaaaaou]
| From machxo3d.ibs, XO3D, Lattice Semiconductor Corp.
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|   Model lvc330s160caaaaaaaou
[Model] lvc330s160caaaaaaaou
Model_type Output
Polarity   Non-Inverting
Enable   Active-High
Vmeas =  1.650V
Cref =  0.0F
Rref =  1.000M
Vref =  0.0V
C_comp   4.200pF   3.800pF   7.500pF
[Temperature Range]   25.000   0.105k   -40.000
[Voltage Range]   3.300V   3.140V   3.470V
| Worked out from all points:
|   slope of the pulldown table from 0 to 0.495 V, typ, clamps not added: 12.1 ohm
|   slope of the pullup table from 0 to 0.495 V, typ, clamps not added: 13.4 ohm
|   rising waveform, R_fixture 50.000, V_fixture 0.0: 20-80 % time 284ps typ, 487ps min, 150ps max; typ from 0 V to 2.57 V
|   rising waveform, R_fixture 50.000, V_fixture 3.300: 20-80 % time 292ps typ, 344ps min, 181ps max; typ from 0.668 V to 3.3 V
|   falling waveform, R_fixture 50.000, V_fixture 3.300: 20-80 % time 464ps typ, 829ps min, 251ps max; typ from 3.3 V to 0.668 V
|   falling waveform, R_fixture 50.000, V_fixture 0.0: 20-80 % time 295ps typ, 359ps min, 197ps max; typ from 2.57 V to 0 V
[Pulldown]
|Voltage   I(typ)   I(min)   I(max)
-3.3V     -4.508A    -3.483A    -6.264A
-1.1V     -430mA     -440.6mA   -433.4mA
-1V       -282.5mA   -321.4mA   -261.4mA
-900mV    -168.1mA   -213.9mA   -168.3mA
-800mV    -102.2mA   -127.5mA   -140.7mA
-600mV    -61.61mA   -43.29mA   -90.23mA
-400mV    -36.65mA   -25.53mA   -53.02mA
1.2V      77.69mA    53.11mA    113.9mA
4.4V      124mA      94.5mA     167.9mA
5.2V      188.6mA    141.7mA    266.9mA
6V        288.6mA    209.7mA    426.9mA
6.6V      386.4mA    272.2mA    586.2mA
[Pullup]
|Voltage   I(typ)   I(min)   I(max)
-3.3V     254.4mA    173.9mA    420.2mA
-2.4V     245.1mA    173.9mA    396mA
800mV     -54.95mA   -40.67mA   -86.23mA
3.7V      -102mA     -75.68mA   -168.9mA
3.9V      -113.4mA   -143.5mA   -171.5mA
4.1V      -146.7mA   -338.7mA   -195.2mA
4.2V      -224.4mA   -457.7mA   -214.8mA
4.4V      -521mA     -713.3mA   -268.6mA
4.5V      -691.6mA   -845.9mA   -420.8mA
4.6V      -867.9mA   -980.3mA   -645.1mA
4.7V      -1.048A    -1.116A    -890.7mA
6.6V      -4.617A    -3.787A    -5.985A
[Ramp]
| variable   typ   min   max
dV/dt_r   1.540/0.281n   1.339/0.484n   1.776/0.149n
dV/dt_f   1.578/0.464n   1.345/0.828n   1.789/0.251n
R_load = 50.000
[Rising Waveform]
R_fixture= 50.000
V_fixture= 0.0
V_fixture_min= 0.0
V_fixture_max= 0.0
|time   V(typ)   V(min)   V(max)
0s        10.33nV    27.72nV    115.7nV
657ps     211.6uV    13.88uV    -6.902mV
940ps     -56.25mV   38.84uV    2.624V
1.135ns   37.11mV    153.2uV    2.873V
1.32ns    856.7mV    -25.74mV   2.922V
1.522ns   1.978V     -45.22mV   2.942V
1.738ns   2.396V     -15.65mV   2.952V
2.546ns   2.554V     1.863V     2.959V
3.341ns   2.565V     2.195V     2.959V
20ns      2.567V     2.232V     2.959V
[Rising Waveform]
R_fixture= 50.000
V_fixture= 3.300
V_fixture_min= 3.140
V_fixture_max= 3.470
|time   V(typ)   V(min)   V(max)
0s        668.3mV    898.5mV    486.2mV
523ps     668.3mV    898.5mV    506.4mV
789ps     658mV      898.5mV    3.125V
866ps     765mV      898.5mV    3.348V
1.09ns    2.358V     898.9mV    3.437V
1.3ns     3.083V     920.4mV    3.455V
1.38ns    3.186V     1.249V     3.458V
1.644ns   3.265V     2.539V     3.464V
2.246ns   3.294V     3.092V     3.468V
20ns      3.299V     3.14V      3.468V
[Falling Waveform]
R_fixture= 50.000
V_fixture= 3.300
V_fixture_min= 3.140
V_fixture_max= 3.470
|time   V(typ)   V(min)   V(max)
0s        3.299V     3.14V      3.468V
663ps     3.299V     3.14V      3.521V
1.096ns   3.369V     3.139V     826.4mV
1.254ns   3.104V     3.141V     590.3mV
1.487ns   2.313V     3.175V     523.6mV
1.751ns   1.378V     3.204V     500mV
2.041ns   858mV      3.027V     491.5mV
3.167ns   678.5mV    1.265V     486.3mV
4.126ns   669.6mV    951.4mV    486.1mV
20ns      668.3mV    898.5mV    486.1mV
[Falling Waveform]
R_fixture= 50.000
V_fixture= 0.0
V_fixture_min= 0.0
V_fixture_max= 0.0
|time   V(typ)   V(min)   V(max)
0s        2.567V     2.232V     2.959V
539ps     2.567V     2.232V     2.958V
820ps     2.567V     2.232V     390mV
918ps     2.491V     2.232V     91.53mV
1.066ns   1.307V     2.232V     32.73mV
1.455ns   99.7mV     2.233V     6.409mV
1.841ns   15.86mV    592.5mV    1.526mV
2.164ns   5.929mV    153.8mV    505.6uV
2.644ns   1.629mV    18.53mV    174.2uV
20ns      42.94nV    145.2nV    120nV
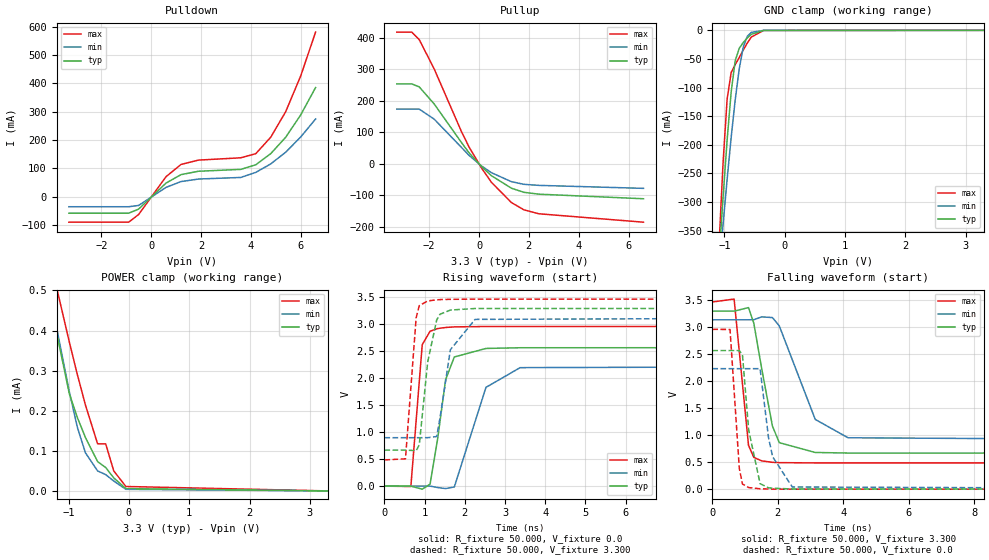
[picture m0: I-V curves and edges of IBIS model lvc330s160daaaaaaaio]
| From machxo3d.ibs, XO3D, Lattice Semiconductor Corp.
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|   Model lvc330s160daaaaaaaio
[Model] lvc330s160daaaaaaaio
Model_type I/O
Polarity   Non-Inverting
Enable   Active-Low
Vinl =  0.800V
Vinh =  2.000V
Vmeas =  1.650V
Cref =  0.0F
Rref =  1.000M
Vref =  0.0V
C_comp   4.200pF   3.800pF   7.500pF
[Temperature Range]   25.000   0.105k   -40.000
[Voltage Range]   3.300V   3.140V   3.470V
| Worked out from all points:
|   slope of the pulldown table from 0 to 0.495 V, typ, clamps not added: 12.2 ohm
|   slope of the pullup table from 0 to 0.495 V, typ, clamps not added: 13.4 ohm
|   GND clamp passes 1 mA (typ) near -0.43 V on its own axis
|   POWER clamp passes 1 mA (typ) near -1.85 V on its own axis
|   rising waveform, R_fixture 50.000, V_fixture 0.0: 20-80 % time 284ps typ, 487ps min, 150ps max; typ from 0 V to 2.57 V
|   rising waveform, R_fixture 50.000, V_fixture 3.300: 20-80 % time 292ps typ, 344ps min, 182ps max; typ from 0.668 V to 3.3 V
|   falling waveform, R_fixture 50.000, V_fixture 3.300: 20-80 % time 465ps typ, 831ps min, 253ps max; typ from 3.3 V to 0.668 V
|   falling waveform, R_fixture 50.000, V_fixture 0.0: 20-80 % time 301ps typ, 364ps min, 198ps max; typ from 2.57 V to 0 V
[Pulldown]
|Voltage   I(typ)   I(min)   I(max)
-3.3V     -58.64mA   -35.81mA   -90.41mA
-900mV    -58.64mA   -35.81mA   -90.41mA
-500mV    -44.08mA   -31.23mA   -63.19mA
600mV     47.81mA    32.63mA    70.46mA
1.2V      77.59mA    53.08mA    113.6mA
1.9V      89.57mA    62.04mA    128.9mA
3.6V      96.17mA    67.67mA    137.1mA
4.2V      112.4mA    85.6mA     151.6mA
4.8V      151.7mA    115.4mA    209.7mA
5.4V      209.6mA    156.8mA    299.9mA
6V        288.2mA    210.3mA    425.6mA
6.6V      385.3mA    274.1mA    581.2mA
[Pullup]
|Voltage   I(typ)   I(min)   I(max)
-3.3V     254.2mA    174.2mA    418.6mA
-2.7V     254.2mA    174.2mA    418.6mA
-2.4V     244.7mA    174.2mA    394.8mA
-1.8V     190.6mA    142.3mA    301.9mA
-700mV    67.45mA    52.16mA    101.9mA
-400mV    35.48mA    27.29mA    53.85mA
100mV     -8.293mA   -6.216mA   -12.85mA
500mV     -37.38mA   -27.82mA   -58.35mA
1.3V      -76.97mA   -56.19mA   -122.5mA
1.8V      -89.97mA   -64.6mA    -145.5mA
2.4V      -95.88mA   -67.93mA   -158.1mA
6.6V      -110.4mA   -77.4mA    -184.8mA
[GND_clamp]
|Voltage   I(typ)   I(min)   I(max)
-3.3V     -4.507A    -3.482A    -6.263A
-1.089V   -398.4mA   -420.6mA   -374.7mA
-1.022V   -290.7mA   -338.6mA   -230.6mA
-955mV    -191.4mA   -260.2mA   -120.1mA
-888mV    -107.5mA   -187mA     -73.7mA
-821mV    -53mA      -121.4mA   -59.85mA
-754mV    -31.41mA   -66.94mA   -47.47mA
-687mV    -21.17mA   -28.82mA   -34.25mA
-620mV    -13.21mA   -10.23mA   -22mA
-553mV    -6.875mA   -3.578mA   -11.73mA
-352mV    -176.3uA   -89.98uA   -279uA
3.3V      50.87nA    0A         -26.43uA
[POWER_clamp]
|Voltage   I(typ)   I(min)   I(max)
-3.3V     3.967mA    2.512mA    11.53mA
-1.323V   507.3uA    506.4uA    605.6uA
-1.256V   446.6uA    452.8uA    548.7uA
-1.189V   387.7uA    399.8uA    501.1uA
-988mV    242.5uA    247.5uA    371.4uA
-854mV    182.6uA    158.2uA    289.7uA
-720mV    133.1uA    94.82uA    213.9uA
-519mV    73.06uA    49.89uA    117.5uA
-385mV    58.36uA    40.66uA    117.5uA
-251mV    32.53uA    24.74uA    49.87uA
-50mV     5.761uA    3.987uA    11.09uA
3.3V      0A         0A         0A
[Ramp]
| variable   typ   min   max
dV/dt_r   1.541/0.281n   1.340/0.485n   1.777/0.149n
dV/dt_f   1.579/0.466n   1.345/0.832n   1.790/0.252n
R_load = 50.000
[Rising Waveform]
R_fixture= 50.000
V_fixture= 0.0
V_fixture_min= 0.0
V_fixture_max= 0.0
|time   V(typ)   V(min)   V(max)
0s        10.33nV    27.72nV    115.7nV
657ps     227.8uV    14.63uV    -6.898mV
940ps     -56.24mV   38.65uV    2.624V
1.135ns   37.1mV     159.3uV    2.873V
1.324ns   881.1mV    -25.75mV   2.923V
1.521ns   1.974V     -45.21mV   2.943V
1.738ns   2.396V     -15.21mV   2.954V
2.525ns   2.554V     1.832V     2.961V
3.375ns   2.567V     2.198V     2.962V
20ns      2.569V     2.234V     2.962V
[Rising Waveform]
R_fixture= 50.000
V_fixture= 3.300
V_fixture_min= 3.140
V_fixture_max= 3.470
|time   V(typ)   V(min)   V(max)
0s        668.3mV    898.5mV    486.2mV
523ps     668.3mV    898.5mV    506.4mV
789ps     658mV      898.5mV    3.125V
866ps     765mV      898.5mV    3.348V
1.076ns   2.304V     898.9mV    3.435V
1.3ns     3.084V     920.4mV    3.456V
1.382ns   3.188V     1.264V     3.46V
1.64ns    3.266V     2.53V      3.465V
2.254ns   3.295V     3.093V     3.469V
20ns      3.3V       3.14V      3.47V
[Falling Waveform]
R_fixture= 50.000
V_fixture= 3.300
V_fixture_min= 3.140
V_fixture_max= 3.470
|time   V(typ)   V(min)   V(max)
0s        3.3V       3.14V      3.47V
664ps     3.3V       3.14V      3.524V
1.104ns   3.366V     3.14V      811.1mV
1.266ns   3.075V     3.141V     589.2mV
1.507ns   2.232V     3.194V     524.6mV
1.834ns   1.171V     3.181V     497.8mV
2.043ns   861.8mV    3.027V     491.8mV
3.141ns   680.3mV    1.293V     486.4mV
4.143ns   669.7mV    952.7mV    486.1mV
20ns      668.3mV    898.5mV    486.1mV
[Falling Waveform]
R_fixture= 50.000
V_fixture= 0.0
V_fixture_min= 0.0
V_fixture_max= 0.0
|time   V(typ)   V(min)   V(max)
0s        2.569V     2.234V     2.962V
539ps     2.569V     2.234V     2.961V
823ps     2.569V     2.234V     384.9mV
919ps     2.49V      2.234V     95.69mV
1.109ns   1.097V     2.234V     29.06mV
1.457ns   102.5mV    2.234V     7.271mV
1.714ns   25.92mV    957.9mV    2.832mV
1.84ns    17.44mV    600.9mV    1.868mV
2.439ns   3.58mV     40.76mV    280.1uV
20ns      44.18nV    145.8nV    124.4nV
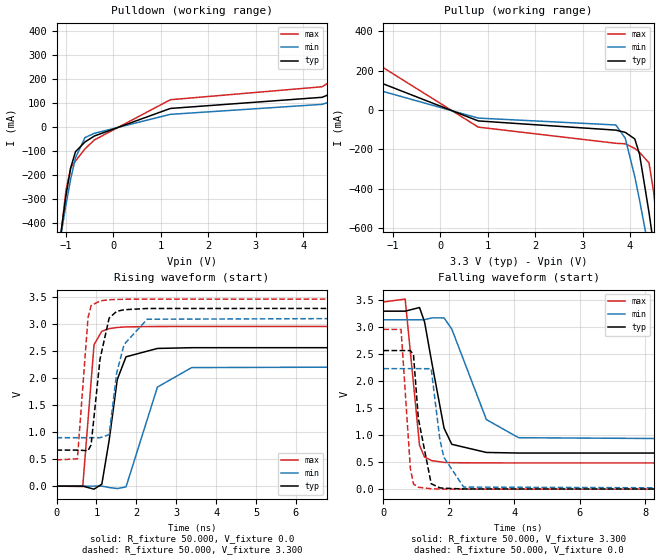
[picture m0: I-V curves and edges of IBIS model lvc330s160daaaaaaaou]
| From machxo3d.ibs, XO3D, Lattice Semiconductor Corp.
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|   Model lvc330s160daaaaaaaou
[Model] lvc330s160daaaaaaaou
Model_type Output
Polarity   Non-Inverting
Enable   Active-High
Vmeas =  1.650V
Cref =  0.0F
Rref =  1.000M
Vref =  0.0V
C_comp   4.200pF   3.800pF   7.500pF
[Temperature Range]   25.000   0.105k   -40.000
[Voltage Range]   3.300V   3.140V   3.470V
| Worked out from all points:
|   slope of the pulldown table from 0 to 0.495 V, typ, clamps not added: 12.1 ohm
|   slope of the pullup table from 0 to 0.495 V, typ, clamps not added: 13.3 ohm
|   rising waveform, R_fixture 50.000, V_fixture 0.0: 20-80 % time 284ps typ, 487ps min, 150ps max; typ from 0 V to 2.57 V
|   rising waveform, R_fixture 50.000, V_fixture 3.300: 20-80 % time 292ps typ, 345ps min, 182ps max; typ from 0.668 V to 3.3 V
|   falling waveform, R_fixture 50.000, V_fixture 3.300: 20-80 % time 467ps typ, 832ps min, 253ps max; typ from 3.3 V to 0.668 V
|   falling waveform, R_fixture 50.000, V_fixture 0.0: 20-80 % time 298ps typ, 362ps min, 198ps max; typ from 2.57 V to 0 V
[Pulldown]
|Voltage   I(typ)   I(min)   I(max)
-3.3V     -4.508A    -3.483A    -6.264A
-1.1V     -430mA     -440.6mA   -433.4mA
-1V       -282.5mA   -321.4mA   -261.4mA
-900mV    -168.1mA   -213.9mA   -168.3mA
-800mV    -102.2mA   -127.5mA   -140.7mA
-600mV    -61.61mA   -43.29mA   -90.23mA
-400mV    -36.65mA   -25.53mA   -53.02mA
1.2V      77.69mA    53.11mA    113.9mA
4.4V      124mA      94.74mA    167.8mA
5.2V      189.1mA    142.8mA    267mA
6V        290.1mA    212.3mA    427.9mA
6.6V      389.2mA    276.9mA    588.3mA
[Pullup]
|Voltage   I(typ)   I(min)   I(max)
-3.3V     255.9mA    175.6mA    421.5mA
-2.4V     246.2mA    175.6mA    396.7mA
800mV     -55.13mA   -40.76mA   -86.59mA
3.7V      -102mA     -75.68mA   -168.9mA
3.9V      -113.4mA   -143.5mA   -171.5mA
4.1V      -146.7mA   -338.7mA   -195.2mA
4.2V      -224.4mA   -457.7mA   -214.8mA
4.4V      -521mA     -713.3mA   -268.6mA
4.5V      -691.6mA   -845.9mA   -420.8mA
4.6V      -867.9mA   -980.3mA   -645.1mA
4.7V      -1.048A    -1.116A    -890.7mA
6.6V      -4.617A    -3.787A    -5.985A
[Ramp]
| variable   typ   min   max
dV/dt_r   1.541/0.281n   1.340/0.485n   1.777/0.149n
dV/dt_f   1.579/0.466n   1.345/0.832n   1.790/0.252n
R_load = 50.000
[Rising Waveform]
R_fixture= 50.000
V_fixture= 0.0
V_fixture_min= 0.0
V_fixture_max= 0.0
|time   V(typ)   V(min)   V(max)
0s        10.33nV    27.72nV    115.7nV
657ps     211.6uV    13.86uV    -6.902mV
940ps     -56.25mV   38.84uV    2.624V
1.135ns   37.11mV    153.2uV    2.873V
1.32ns    856.7mV    -25.74mV   2.922V
1.522ns   1.978V     -45.22mV   2.943V
1.741ns   2.399V     -14.31mV   2.954V
2.528ns   2.554V     1.837V     2.961V
3.387ns   2.568V     2.199V     2.962V
20ns      2.569V     2.234V     2.962V
[Rising Waveform]
R_fixture= 50.000
V_fixture= 3.300
V_fixture_min= 3.140
V_fixture_max= 3.470
|time   V(typ)   V(min)   V(max)
0s        668.3mV    898.5mV    486.2mV
523ps     668.3mV    898.5mV    506.4mV
789ps     658mV      898.5mV    3.125V
866ps     765mV      898.5mV    3.348V
1.09ns    2.358V     898.9mV    3.437V
1.318ns   3.116V     955.2mV    3.457V
1.508ns   3.243V     2.102V     3.463V
1.692ns   3.272V     2.628V     3.466V
2.271ns   3.295V     3.096V     3.469V
20ns      3.3V       3.14V      3.47V
[Falling Waveform]
R_fixture= 50.000
V_fixture= 3.300
V_fixture_min= 3.140
V_fixture_max= 3.470
|time   V(typ)   V(min)   V(max)
0s        3.3V       3.14V      3.47V
664ps     3.3V       3.14V      3.524V
1.103ns   3.367V     3.14V      814.4mV
1.257ns   3.1V       3.142V     593.9mV
1.488ns   2.312V     3.176V     527.5mV
1.852ns   1.131V     3.175V     497mV
2.088ns   831.7mV    2.968V     490.8mV
3.144ns   680.4mV    1.29V      486.3mV
4.127ns   669.8mV    953.8mV    486.2mV
20ns      668.3mV    898.5mV    486.2mV
[Falling Waveform]
R_fixture= 50.000
V_fixture= 0.0
V_fixture_min= 0.0
V_fixture_max= 0.0
|time   V(typ)   V(min)   V(max)
0s        2.569V     2.234V     2.962V
539ps     2.569V     2.234V     2.961V
823ps     2.569V     2.234V     384.8mV
919ps     2.49V      2.234V     95.67mV
1.066ns   1.314V     2.234V     35.27mV
1.459ns   100.8mV    2.233V     7.262mV
1.724ns   24.63mV    920.3mV    2.917mV
1.844ns   17.35mV    592.8mV    1.651mV
2.45ns    4.134mV    38.54mV    211.5uV
20ns      44.51nV    146.2nV    122.1nV
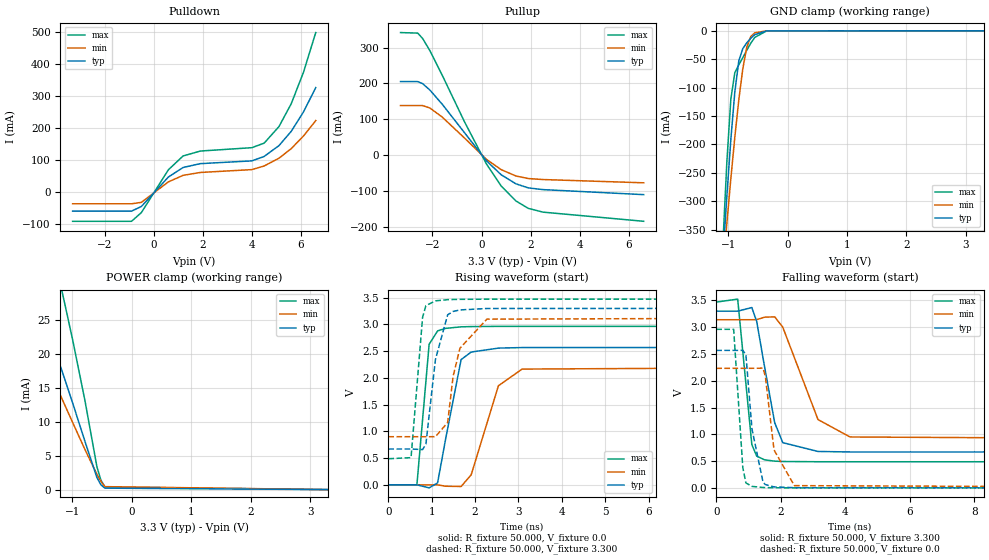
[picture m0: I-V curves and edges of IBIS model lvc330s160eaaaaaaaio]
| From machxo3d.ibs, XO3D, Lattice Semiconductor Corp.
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|   Model lvc330s160eaaaaaaaio
[Model] lvc330s160eaaaaaaaio
Model_type I/O
Polarity   Non-Inverting
Enable   Active-Low
Vinl =  0.800V
Vinh =  2.000V
Vmeas =  1.650V
Cref =  0.0F
Rref =  1.000M
Vref =  0.0V
C_comp   4.200pF   3.800pF   7.500pF
[Temperature Range]   25.000   0.105k   -40.000
[Voltage Range]   3.300V   3.140V   3.470V
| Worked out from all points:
|   slope of the pulldown table from 0 to 0.495 V, typ, clamps not added: 12.2 ohm
|   slope of the pullup table from 0 to 0.495 V, typ, clamps not added: 13.4 ohm
|   GND clamp passes 1 mA (typ) near -0.43 V on its own axis
|   POWER clamp passes 1 mA (typ) near -0.54 V on its own axis
|   rising waveform, R_fixture 50.000, V_fixture 0.0: 20-80 % time 283ps typ, 487ps min, 150ps max; typ from 0 V to 2.57 V
|   rising waveform, R_fixture 50.000, V_fixture 3.300: 20-80 % time 287ps typ, 343ps min, 181ps max; typ from 0.669 V to 3.3 V
|   falling waveform, R_fixture 50.000, V_fixture 3.300: 20-80 % time 463ps typ, 831ps min, 251ps max; typ from 3.3 V to 0.669 V
|   falling waveform, R_fixture 50.000, V_fixture 0.0: 20-80 % time 296ps typ, 360ps min, 197ps max; typ from 2.57 V to 0 V
[Pulldown]
|Voltage   I(typ)   I(min)   I(max)
-3.3V     -58.64mA   -35.81mA   -90.41mA
-900mV    -58.64mA   -35.81mA   -90.41mA
-500mV    -44.08mA   -31.23mA   -63.19mA
600mV     47.81mA    32.63mA    70.46mA
1.2V      77.59mA    53.08mA    113.6mA
1.9V      89.57mA    62.04mA    128.9mA
4V        98.2mA     70.91mA    139.4mA
4.5V      112.1mA    82.29mA    153.7mA
5.1V      145.7mA    106.4mA    205mA
5.6V      190.2mA    136.3mA    276.3mA
6.1V      250.9mA    175.9mA    374.7mA
6.6V      327mA      224mA      498.7mA
[Pullup]
|Voltage   I(typ)   I(min)   I(max)
-3.3V     205mA      138.1mA    341.8mA
-2.6V     205mA      138.1mA    340.3mA
-2.4V     199.3mA    138.1mA    325.3mA
-2.1V     181.1mA    131.2mA    290.9mA
-1.6V     141.7mA    105.8mA    222.5mA
-700mV    62.84mA    47.92mA    93.52mA
200mV     -16.17mA   -12.1mA    -25.1mA
800mV     -55.05mA   -40.71mA   -86.48mA
1.4V      -80.26mA   -58.42mA   -128.1mA
1.9V      -91.56mA   -65.51mA   -148.7mA
2.5V      -96.41mA   -68.28mA   -159.2mA
6.6V      -110.4mA   -77.4mA    -184.8mA
[GND_clamp]
|Voltage   I(typ)   I(min)   I(max)
-3.3V     -4.507A    -3.482A    -6.263A
-1.089V   -398.4mA   -420.6mA   -374.7mA
-1.022V   -290.7mA   -338.6mA   -230.6mA
-955mV    -191.3mA   -260.2mA   -120mA
-888mV    -107.5mA   -187mA     -73.64mA
-821mV    -52.96mA   -121.4mA   -59.79mA
-754mV    -31.36mA   -66.92mA   -47.4mA
-687mV    -21.12mA   -28.79mA   -34.18mA
-620mV    -13.16mA   -10.19mA   -21.93mA
-553mV    -6.814mA   -3.53mA    -11.64mA
-352mV    -96.36uA   -46.21uA   -149.8uA
3.3V      0A         0A         0A
[POWER_clamp]
|Voltage   I(typ)   I(min)   I(max)
-3.3V     59.07mA    46.89mA    89.53mA
-1.993V   37.2mA     28.86mA    58.21mA
-1.926V   35.72mA    27.66mA    56.06mA
-1.591V   27.93mA    21.43mA    44.68mA
-1.189V   17.86mA    13.66mA    29.77mA
-1.122V   16.11mA    12.35mA    27.14mA
-988mV    12.56mA    9.745mA    21.76mA
-787mV    7.078mA    5.887mA    13.07mA
-586mV    1.773mA    2.247mA    3.338mA
-519mV    707uA      1.205mA    1.383mA
-452mV    214.8uA    435.5uA    392.3uA
3.3V      0A         0A         0A
[Ramp]
| variable   typ   min   max
dV/dt_r   1.541/0.281n   1.340/0.484n   1.777/0.149n
dV/dt_f   1.578/0.464n   1.345/0.828n   1.789/0.251n
R_load = 50.000
[Rising Waveform]
R_fixture= 50.000
V_fixture= 0.0
V_fixture_min= 0.0
V_fixture_max= 0.0
|time   V(typ)   V(min)   V(max)
0s        10.54nV    27.99nV    119.6nV
657ps     228.9uV    14.68uV    -7.34mV
940ps     -56.33mV   38.7uV     2.627V
1.135ns   36.8mV     160.3uV    2.876V
1.32ns    857.3mV    -25.75mV   2.924V
1.677ns   2.34V      -30.81mV   2.952V
1.909ns   2.481V     187mV      2.957V
2.537ns   2.555V     1.851V     2.961V
3.083ns   2.565V     2.163V     2.961V
20ns      2.568V     2.233V     2.961V
[Rising Waveform]
R_fixture= 50.000
V_fixture= 3.300
V_fixture_min= 3.140
V_fixture_max= 3.470
|time   V(typ)   V(min)   V(max)
0s        669.4mV    899.2mV    487.7mV
523ps     669.4mV    899.2mV    508.1mV
789ps     659.1mV    899.2mV    3.13V
865ps     761.5mV    899.2mV    3.349V
1.085ns   2.343V     899.5mV    3.438V
1.367ns   3.177V     1.165V     3.46V
1.492ns   3.24V      2.025V     3.463V
1.65ns    3.268V     2.553V     3.466V
2.27ns    3.295V     3.096V     3.469V
20ns      3.3V       3.14V      3.47V
[Falling Waveform]
R_fixture= 50.000
V_fixture= 3.300
V_fixture_min= 3.140
V_fixture_max= 3.470
|time   V(typ)   V(min)   V(max)
0s        3.3V       3.14V      3.47V
664ps     3.3V       3.14V      3.525V
1.103ns   3.368V     3.14V      808.8mV
1.255ns   3.106V     3.142V     592.3mV
1.501ns   2.252V     3.188V     523.2mV
1.814ns   1.214V     3.194V     498.8mV
2.063ns   844.4mV    3.001V     492.5mV
3.157ns   679.7mV    1.275V     487.8mV
4.15ns    670.7mV    950.5mV    487.6mV
20ns      669.4mV    899.2mV    487.6mV
[Falling Waveform]
R_fixture= 50.000
V_fixture= 0.0
V_fixture_min= 0.0
V_fixture_max= 0.0
|time   V(typ)   V(min)   V(max)
0s        2.568V     2.233V     2.961V
539ps     2.568V     2.233V     2.961V
823ps     2.568V     2.233V     377.9mV
919ps     2.488V     2.233V     92.75mV
1.107ns   1.101V     2.233V     27.5mV
1.451ns   104.6mV    2.236V     6.916mV
1.522ns   61.77mV    2.086V     5.281mV
1.791ns   18.04mV    709.1mV    2.054mV
2.423ns   2.881mV    41.58mV    237.1uV
20ns      47.49nV    150nV      132.7nV
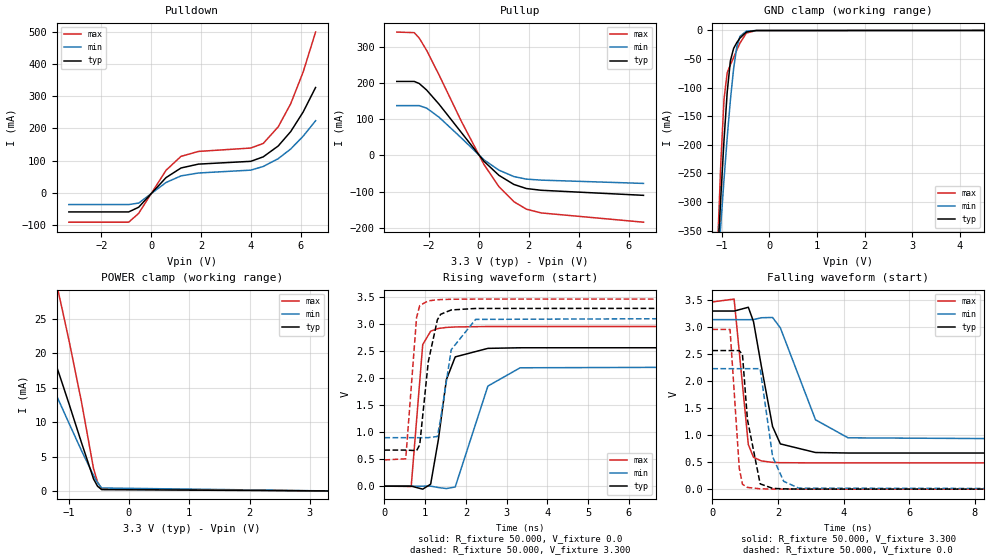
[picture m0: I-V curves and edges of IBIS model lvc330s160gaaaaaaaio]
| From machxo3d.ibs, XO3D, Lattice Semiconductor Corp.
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|   Model lvc330s160gaaaaaaaio
[Model] lvc330s160gaaaaaaaio
Model_type I/O
Polarity   Non-Inverting
Enable   Active-Low
Vinl =  0.800V
Vinh =  2.000V
Vmeas =  1.650V
Cref =  0.0F
Rref =  1.000M
Vref =  0.0V
C_comp   4.200pF   3.800pF   7.500pF
[Temperature Range]   25.000   0.105k   -40.000
[Voltage Range]   3.300V   3.140V   3.470V
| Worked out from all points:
|   slope of the pulldown table from 0 to 0.495 V, typ, clamps not added: 12.2 ohm
|   slope of the pullup table from 0 to 0.495 V, typ, clamps not added: 13.4 ohm
|   GND clamp passes 1 mA (typ) near -0.43 V on its own axis
|   POWER clamp passes 1 mA (typ) near -0.54 V on its own axis
|   rising waveform, R_fixture 50.000, V_fixture 0.0: 20-80 % time 283ps typ, 487ps min, 150ps max; typ from 0 V to 2.57 V
|   rising waveform, R_fixture 50.000, V_fixture 3.300: 20-80 % time 292ps typ, 348ps min, 181ps max; typ from 0.668 V to 3.3 V
|   falling waveform, R_fixture 50.000, V_fixture 3.300: 20-80 % time 463ps typ, 829ps min, 251ps max; typ from 3.3 V to 0.668 V
|   falling waveform, R_fixture 50.000, V_fixture 0.0: 20-80 % time 298ps typ, 359ps min, 197ps max; typ from 2.57 V to 0 V
[Pulldown]
|Voltage   I(typ)   I(min)   I(max)
-3.3V     -58.64mA   -35.81mA   -90.41mA
-900mV    -58.64mA   -35.81mA   -90.41mA
-500mV    -44.08mA   -31.23mA   -63.19mA
600mV     47.81mA    32.63mA    70.46mA
1.2V      77.59mA    53.08mA    113.6mA
1.9V      89.57mA    62.04mA    128.9mA
4V        98.19mA    70.91mA    139.4mA
4.5V      112.1mA    82.29mA    153.7mA
5.1V      145.7mA    106.4mA    205mA
5.6V      190.2mA    136.3mA    276.3mA
6.1V      250.9mA    175.9mA    374.7mA
6.6V      327mA      224mA      498.7mA
[Pullup]
|Voltage   I(typ)   I(min)   I(max)
-3.3V     205.1mA    138.1mA    341.8mA
-2.6V     205.1mA    138.1mA    340.3mA
-2.4V     199.4mA    138.1mA    325.3mA
-2.1V     181.1mA    131.2mA    290.9mA
-1.6V     141.7mA    105.8mA    222.5mA
-700mV    62.85mA    47.92mA    93.53mA
200mV     -16.17mA   -12.1mA    -25.1mA
800mV     -55.05mA   -40.71mA   -86.48mA
1.4V      -80.26mA   -58.42mA   -128.1mA
1.9V      -91.56mA   -65.51mA   -148.7mA
2.5V      -96.41mA   -68.28mA   -159.2mA
6.6V      -110.4mA   -77.4mA    -184.8mA
[GND_clamp]
|Voltage   I(typ)   I(min)   I(max)
-3.3V     -4.507A    -3.482A    -6.263A
-1.089V   -398.4mA   -420.6mA   -374.7mA
-1.022V   -290.7mA   -338.6mA   -230.6mA
-955mV    -191.4mA   -260.2mA   -120.1mA
-888mV    -107.5mA   -187mA     -73.7mA
-821mV    -53mA      -121.4mA   -59.85mA
-754mV    -31.41mA   -66.94mA   -47.47mA
-687mV    -21.17mA   -28.82mA   -34.25mA
-620mV    -13.21mA   -10.23mA   -22mA
-486mV    -2.63mA    -1.112mA   -4.479mA
-285mV    -80.91uA   -42.41uA   -152.3uA
6.6V      121.2uA    55.84uA    291.2uA
[POWER_clamp]
|Voltage   I(typ)   I(min)   I(max)
-3.3V     59.17mA    46.96mA    89.71mA
-1.993V   37.21mA    28.87mA    58.18mA
-1.926V   35.73mA    27.67mA    56.02mA
-1.591V   27.93mA    21.43mA    44.63mA
-1.189V   17.84mA    13.65mA    29.69mA
-1.122V   16.09mA    12.35mA    27.06mA
-988mV    12.53mA    9.74mA     21.66mA
-787mV    7.047mA    5.88mA     12.98mA
-586mV    1.736mA    2.238mA    3.233mA
-519mV    672uA      1.196mA    1.278mA
-452mV    189uA      428.3uA    309.6uA
3.3V      0A         0A         0A
[Ramp]
| variable   typ   min   max
dV/dt_r   1.540/0.281n   1.339/0.484n   1.776/0.149n
dV/dt_f   1.578/0.464n   1.345/0.828n   1.789/0.251n
R_load = 50.000
[Rising Waveform]
R_fixture= 50.000
V_fixture= 0.0
V_fixture_min= 0.0
V_fixture_max= 0.0
|time   V(typ)   V(min)   V(max)
0s        10.33nV    27.72nV    115.7nV
657ps     227.8uV    14.64uV    -6.898mV
940ps     -56.24mV   38.64uV    2.624V
1.135ns   37.1mV     159.3uV    2.873V
1.323ns   856.6mV    -25.75mV   2.923V
1.521ns   1.974V     -45.21mV   2.942V
1.738ns   2.396V     -15.21mV   2.951V
2.54ns    2.554V     1.855V     2.959V
3.332ns   2.565V     2.194V     2.959V
20ns      2.567V     2.232V     2.959V
[Rising Waveform]
R_fixture= 50.000
V_fixture= 3.300
V_fixture_min= 3.140
V_fixture_max= 3.470
|time   V(typ)   V(min)   V(max)
0s        668.3mV    898.5mV    486.2mV
523ps     668.3mV    898.5mV    506.4mV
789ps     658mV      898.5mV    3.125V
866ps     765mV      898.5mV    3.348V
1.076ns   2.304V     898.9mV    3.435V
1.3ns     3.084V     920.4mV    3.455V
1.38ns    3.186V     1.249V     3.458V
1.64ns    3.266V     2.53V      3.464V
2.238ns   3.294V     3.091V     3.468V
20ns      3.299V     3.14V      3.468V
[Falling Waveform]
R_fixture= 50.000
V_fixture= 3.300
V_fixture_min= 3.140
V_fixture_max= 3.470
|time   V(typ)   V(min)   V(max)
0s        3.299V     3.14V      3.468V
663ps     3.299V     3.14V      3.521V
1.096ns   3.369V     3.139V     826.4mV
1.254ns   3.104V     3.141V     590.4mV
1.493ns   2.278V     3.175V     523mV
1.835ns   1.16V      3.18V      496.2mV
2.072ns   838.5mV    2.988V     490.5mV
3.144ns   678.9mV    1.285V     486.4mV
4.136ns   669.6mV    950.9mV    486.2mV
20ns      668.3mV    898.5mV    486.2mV
[Falling Waveform]
R_fixture= 50.000
V_fixture= 0.0
V_fixture_min= 0.0
V_fixture_max= 0.0
|time   V(typ)   V(min)   V(max)
0s        2.567V     2.232V     2.959V
539ps     2.567V     2.232V     2.958V
820ps     2.567V     2.232V     390.1mV
918ps     2.491V     2.232V     91.57mV
1.069ns   1.29V      2.232V     32.45mV
1.457ns   98.14mV    2.232V     6.317mV
1.837ns   15.19mV    600.7mV    1.729mV
2.174ns   5.532mV    145.6mV    466.4uV
2.63ns    1.668mV    19.39mV    153.7uV
20ns      43.42nV    146.7nV    125.2nV
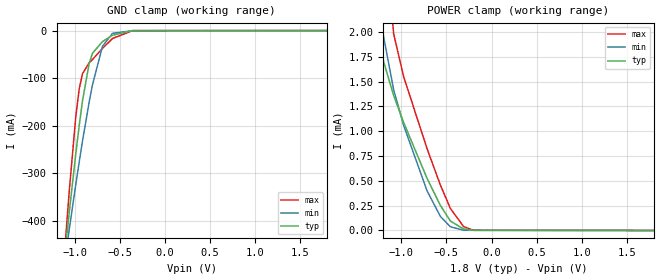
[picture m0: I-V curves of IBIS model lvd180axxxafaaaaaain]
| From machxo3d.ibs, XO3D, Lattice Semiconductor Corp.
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|   Model lvd180axxxafaaaaaain
[Model] lvd180axxxafaaaaaain
Model_type Input
Polarity   Non-Inverting
Enable   Active-High
Vinl =  0.630V
Vinh =  1.170V
C_comp   4.200pF   3.800pF   7.500pF
[Temperature Range]   25.000   0.105k   -40.000
[Voltage Range]   1.800V   1.710V   1.890V
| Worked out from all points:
|   GND clamp passes 1 mA (typ) near -0.43 V on its own axis
|   POWER clamp passes 1 mA (typ) near -0.94 V on its own axis
[GND_clamp]
|Voltage   I(typ)   I(min)   I(max)
-1.8V     -1.831A    -1.488A    -2.421A
-1.097V   -451mA     -469.7mA   -431.6mA
-1.06V    -384.8mA   -420mA     -340.3mA
-986mV    -258.9mA   -323.6mA   -180.7mA
-949mV    -200.9mA   -277.4mA   -123.7mA
-912mV    -148.2mA   -232.8mA   -90.76mA
-838mV    -69.05mA   -150.6mA   -67.91mA
-801mV    -47.74mA   -114.1mA   -60.88mA
-690mV    -23.16mA   -33.02mA   -37.51mA
-579mV    -9.79mA    -5.846mA   -16.62mA
-357mV    -148.7uA   -66.38uA   -242.3uA
1.8V      0A         0A         0A
[POWER_clamp]
|Voltage   I(typ)   I(min)   I(max)
-1.8V     9.805mA    6.292mA    21.89mA
-1.271V   2.077mA    2.399mA    4.682mA
-1.234V   1.861mA    2.168mA    3.79mA
-1.197V   1.7mA      1.95mA     3.092mA
-1.086V   1.36mA     1.418mA    1.981mA
-975mV    1.088mA    1.058mA    1.55mA
-716mV    526uA      400.6uA    825.4uA
-568mV    252.9uA    142.1uA    458.4uA
-457mV    95.28uA    37.76uA    222.2uA
-309mV    14.3uA     2.005uA    38.47uA
-198mV    1.727uA    1.797uA    2.013uA
1.8V      0A         0A         4.279nA
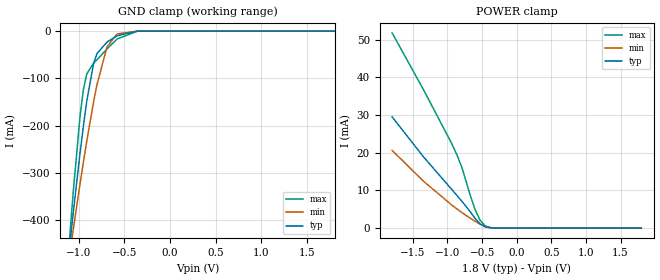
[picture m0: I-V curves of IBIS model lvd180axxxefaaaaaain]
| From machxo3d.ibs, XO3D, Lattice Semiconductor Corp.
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|   Model lvd180axxxefaaaaaain
[Model] lvd180axxxefaaaaaain
Model_type Input
Polarity   Non-Inverting
Enable   Active-High
Vinl =  0.630V
Vinh =  1.170V
C_comp   4.200pF   3.800pF   7.500pF
[Temperature Range]   25.000   0.105k   -40.000
[Voltage Range]   1.800V   1.710V   1.890V
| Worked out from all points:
|   GND clamp passes 1 mA (typ) near -0.43 V on its own axis
|   POWER clamp passes 1 mA (typ) near -0.52 V on its own axis
[GND_clamp]
|Voltage   I(typ)   I(min)   I(max)
-1.8V     -1.831A    -1.488A    -2.421A
-1.097V   -451mA     -469.7mA   -431.6mA
-1.06V    -384.8mA   -420mA     -340.3mA
-986mV    -258.9mA   -323.6mA   -180.7mA
-949mV    -200.9mA   -277.4mA   -123.7mA
-912mV    -148.2mA   -232.8mA   -90.76mA
-838mV    -69.05mA   -150.6mA   -67.91mA
-801mV    -47.74mA   -114.1mA   -60.88mA
-690mV    -23.16mA   -33.02mA   -37.51mA
-579mV    -9.79mA    -5.846mA   -16.62mA
-357mV    -148.7uA   -66.38uA   -242.3uA
1.8V      0A         0A         0A
[POWER_clamp]
|Voltage   I(typ)   I(min)   I(max)
-1.8V     29.51mA    20.63mA    51.76mA
-1.345V   18.87mA    12.41mA    36.66mA
-938mV    10.26mA    6.136mA    22.4mA
-864mV    8.689mA    5.106mA    19.43mA
-790mV    7.087mA    4.117mA    16.01mA
-679mV    4.54mA     2.724mA    9.207mA
-605mV    2.701mA    1.871mA    5.102mA
-531mV    1.131mA    1.1mA      2.169mA
-457mV    338.1uA    470.7uA    629.2uA
-383mV    89.2uA     117.2uA    163.1uA
-272mV    9.185uA    9.485uA    15.71uA
1.8V      0A         0A         4.279nA
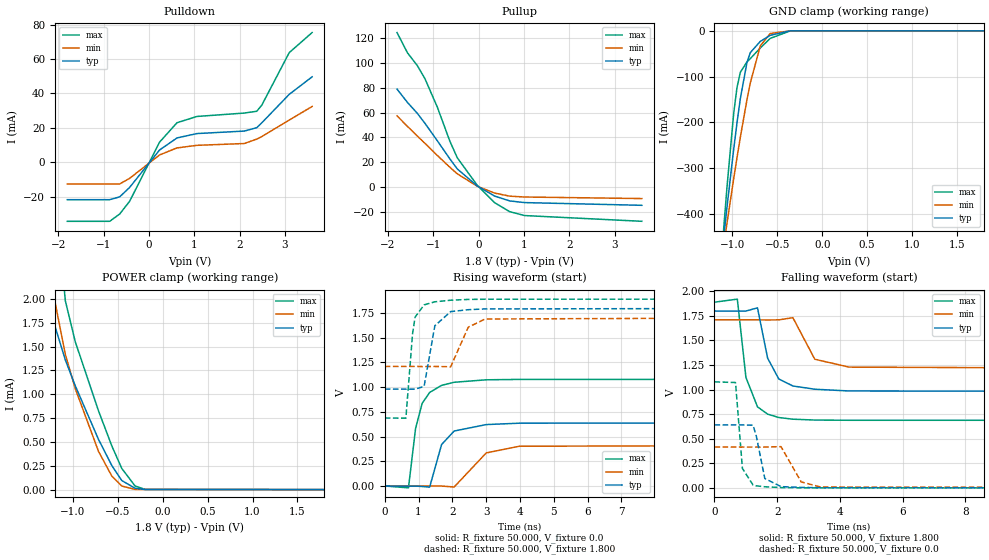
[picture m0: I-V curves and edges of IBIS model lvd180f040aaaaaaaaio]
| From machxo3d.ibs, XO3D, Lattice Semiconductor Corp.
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|   Model lvd180f040aaaaaaaaio
[Model] lvd180f040aaaaaaaaio
Model_type I/O
Polarity   Non-Inverting
Enable   Active-Low
Vinl =  0.630V
Vinh =  1.170V
Vmeas =  0.900V
Cref =  0.0F
Rref =  1.000M
Vref =  0.0V
C_comp   4.200pF   3.800pF   7.500pF
[Temperature Range]   25.000   0.105k   -40.000
[Voltage Range]   1.800V   1.710V   1.890V
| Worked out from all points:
|   slope of the pulldown table from 0 to 0.27 V, typ, clamps not added: 34 ohm
|   slope of the pullup table from 0 to 0.27 V, typ, clamps not added: 45.6 ohm
|   GND clamp passes 1 mA (typ) near -0.43 V on its own axis
|   POWER clamp passes 1 mA (typ) near -0.94 V on its own axis
|   rising waveform, R_fixture 50.000, V_fixture 0.0: 20-80 % time 437ps typ, 499ps min, 361ps max; typ from 0 V to 0.641 V
|   rising waveform, R_fixture 50.000, V_fixture 1.800: 20-80 % time 264ps typ, 401ps min, 162ps max; typ from 0.98 V to 1.8 V
|   falling waveform, R_fixture 50.000, V_fixture 1.800: 20-80 % time 456ps typ, 527ps min, 362ps max; typ from 1.8 V to 0.98 V
|   falling waveform, R_fixture 50.000, V_fixture 0.0: 20-80 % time 211ps typ, 371ps min, 144ps max; typ from 0.641 V to 0 V
[Pulldown]
|Voltage   I(typ)   I(min)   I(max)
-1.8V     -21.78mA   -12.65mA   -34.34mA
-865mV    -21.78mA   -12.65mA   -34.34mA
-645mV    -20.15mA   -12.65mA   -30.11mA
-425mV    -14.65mA   -9.378mA   -22.7mA
235mV     7.083mA    4.214mA    11.64mA
620mV     14.1mA     8.304mA    22.95mA
1.06V     16.64mA    9.805mA    26.58mA
2.105V    18.09mA    10.86mA    28.56mA
2.38V     20.08mA    13.42mA    29.6mA
2.49V     22.88mA    14.9mA     33.15mA
3.095V    39.41mA    24.47mA    63.64mA
3.6V      49.6mA     32.37mA    75.33mA
[Pullup]
|Voltage   I(typ)   I(min)   I(max)
-1.8V     78.9mA     57.32mA    124.5mA
-1.57V    68.17mA    48.86mA    108.2mA
-1.35V    59.28mA    40.99mA    97.73mA
-1.185V   51.37mA    35.2mA     87.37mA
-910mV    37.2mA     25.36mA    64.3mA
-635mV    22.67mA    15.91mA    36.96mA
-470mV    14.53mA    10.59mA    23.5mA
-30mV     777.9uA    534.4uA    1.311mA
355mV     -7.378mA   -4.969mA   -12.72mA
685mV     -11.26mA   -7.415mA   -19.94mA
1.015V    -12.62mA   -8.118mA   -23.07mA
3.6V      -14.81mA   -9.364mA   -27.7mA
[GND_clamp]
|Voltage   I(typ)   I(min)   I(max)
-1.8V     -1.831A    -1.488A    -2.421A
-1.097V   -451mA     -469.7mA   -431.6mA
-1.06V    -384.8mA   -420mA     -340.3mA
-986mV    -258.9mA   -323.6mA   -180.7mA
-949mV    -200.9mA   -277.4mA   -123.7mA
-912mV    -148.2mA   -232.8mA   -90.76mA
-838mV    -69.05mA   -150.6mA   -67.91mA
-801mV    -47.74mA   -114.1mA   -60.88mA
-690mV    -23.16mA   -33.02mA   -37.51mA
-579mV    -9.79mA    -5.846mA   -16.62mA
-357mV    -148.7uA   -66.38uA   -242.3uA
1.8V      0A         0A         0A
[POWER_clamp]
|Voltage   I(typ)   I(min)   I(max)
-1.8V     9.805mA    6.292mA    21.89mA
-1.271V   2.077mA    2.399mA    4.682mA
-1.234V   1.861mA    2.168mA    3.79mA
-1.197V   1.7mA      1.95mA     3.092mA
-1.086V   1.36mA     1.418mA    1.981mA
-975mV    1.088mA    1.058mA    1.55mA
-716mV    526uA      400.6uA    825.4uA
-568mV    252.9uA    142.1uA    458.4uA
-457mV    95.28uA    37.76uA    222.2uA
-309mV    14.3uA     2.005uA    38.47uA
-198mV    1.727uA    1.797uA    2.013uA
1.8V      0A         0A         4.279nA
[Ramp]
| variable   typ   min   max
dV/dt_r   0.384/0.437n   0.249/0.502n   0.647/0.359n
dV/dt_f   0.492/0.449n   0.301/0.515n   0.721/0.363n
R_load = 50.000
[Rising Waveform]
R_fixture= 50.000
V_fixture= 0.0
V_fixture_min= 0.0
V_fixture_max= 0.0
|time   V(typ)   V(min)   V(max)
0s        8.268nV    71.3nV     4.54nV
701ps     -546.2uV   20.36uV    -18.87mV
911ps     -600uV     -4.009uV   581.9mV
1.106ns   -5.237mV   -481.8uV   836mV
1.328ns   -11.42mV   -215.5uV   946mV
1.681ns   419.5mV    -670.1uV   1.018V
2.053ns   556.1mV    -10.14mV   1.049V
3.003ns   621.3mV    334.7mV    1.074V
3.984ns   635.3mV    402.1mV    1.078V
20ns      640.6mV    415.2mV    1.079V
[Rising Waveform]
R_fixture= 50.000
V_fixture= 1.800
V_fixture_min= 1.710
V_fixture_max= 1.890
|time   V(typ)   V(min)   V(max)
0s        979.8mV    1.209V     687.7mV
624ps     979.5mV    1.209V     685.9mV
822ps     978.9mV    1.209V     1.54V
897ps     979.3mV    1.209V     1.708V
1.164ns   1.007V     1.208V     1.832V
1.482ns   1.621V     1.209V     1.863V
1.951ns   1.764V     1.206V     1.879V
2.469ns   1.783V     1.606V     1.887V
2.969ns   1.791V     1.689V     1.889V
20ns      1.8V       1.71V      1.89V
[Falling Waveform]
R_fixture= 50.000
V_fixture= 1.800
V_fixture_min= 1.710
V_fixture_max= 1.890
|time   V(typ)   V(min)   V(max)
0s        1.8V       1.71V      1.89V
729ps     1.799V     1.71V      1.921V
1.003ns   1.8V       1.71V      1.124V
1.372ns   1.832V     1.71V      824.7mV
1.696ns   1.32V      1.709V     750.4mV
2.053ns   1.108V     1.71V      715.9mV
2.502ns   1.037V     1.732V     698.9mV
3.201ns   1.004V     1.309V     690.2mV
4.296ns   986.1mV    1.229V     687.9mV
20ns      979.8mV    1.209V     687.7mV
[Falling Waveform]
R_fixture= 50.000
V_fixture= 0.0
V_fixture_min= 0.0
V_fixture_max= 0.0
|time   V(typ)   V(min)   V(max)
0s        640.6mV    415.2mV    1.079V
671ps     640.2mV    415.2mV    1.072V
891ps     640.2mV    415.1mV    198.1mV
1.231ns   637.4mV    414.9mV    28.4mV
1.334ns   527.5mV    415.1mV    20.51mV
1.606ns   94.68mV    415.3mV    11.02mV
2.123ns   12.65mV    419.5mV    3.061mV
2.767ns   4.947mV    60.19mV    761.5uV
3.39ns    1.809mV    8.434mV    204.6uV
20ns      -268.7nV   -28.66nV   -47.1nV
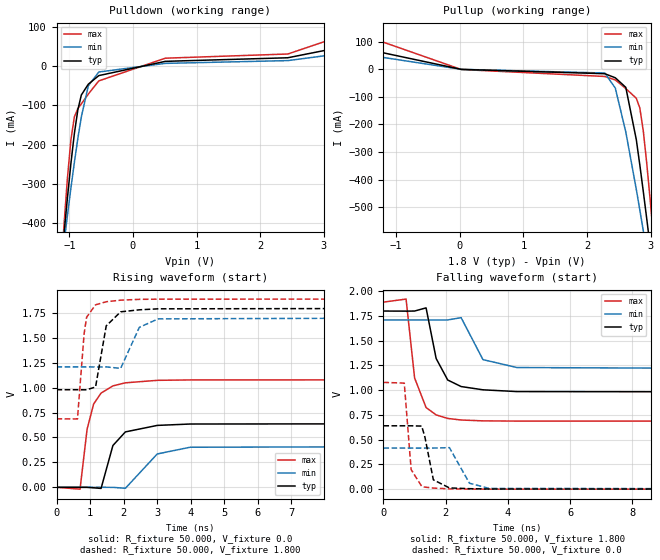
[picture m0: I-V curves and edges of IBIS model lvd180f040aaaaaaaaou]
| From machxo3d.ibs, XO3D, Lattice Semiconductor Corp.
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|   Model lvd180f040aaaaaaaaou
[Model] lvd180f040aaaaaaaaou
Model_type Output
Polarity   Non-Inverting
Enable   Active-High
Vmeas =  0.900V
Cref =  0.0F
Rref =  1.000M
Vref =  0.0V
C_comp   4.200pF   3.800pF   7.500pF
[Temperature Range]   25.000   0.105k   -40.000
[Voltage Range]   1.800V   1.710V   1.890V
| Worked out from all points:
|   slope of the pulldown table from 0 to 0.27 V, typ, clamps not added: 34 ohm
|   slope of the pullup table from 0 to 0.27 V, typ, clamps not added: 45.6 ohm
|   rising waveform, R_fixture 50.000, V_fixture 0.0: 20-80 % time 437ps typ, 499ps min, 360ps max; typ from 0 V to 0.641 V
|   rising waveform, R_fixture 50.000, V_fixture 1.800: 20-80 % time 264ps typ, 401ps min, 162ps max; typ from 0.98 V to 1.8 V
|   falling waveform, R_fixture 50.000, V_fixture 1.800: 20-80 % time 454ps typ, 527ps min, 362ps max; typ from 1.8 V to 0.98 V
|   falling waveform, R_fixture 50.000, V_fixture 0.0: 20-80 % time 211ps typ, 371ps min, 144ps max; typ from 0.641 V to 0 V
[Pulldown]
|Voltage   I(typ)   I(min)   I(max)
-1.8V     -1.832A    -1.488A    -2.422A
-1.085V   -433.5mA   -455.5mA   -411.7mA
-1.03V    -338.2mA   -382.8mA   -288.6mA
-975mV    -249.8mA   -312.6mA   -189.3mA
-920mV    -172.3mA   -246mA     -129.6mA
-865mV    -111.3mA   -184.3mA   -107.8mA
-810mV    -73.34mA   -129.4mA   -95.99mA
-700mV    -45.69mA   -49.6mA    -70.91mA
-535mV    -23.72mA   -14.54mA   -37.26mA
510mV     12.66mA    7.475mA    20.72mA
2.435V    21.8mA     14.56mA    31.41mA
3.6V      59.4mA     39.38mA    95.45mA
[Pullup]
|Voltage   I(typ)   I(min)   I(max)
-1.8V     88.71mA    63.61mA    146.4mA
25mV      -631.9uA   -432.1uA   -1.07mA
2.28V     -16.33mA   -13.87mA   -26.27mA
2.445V    -31.12mA   -68.47mA   -38.92mA
2.61V     -65.91mA   -227.8mA   -70.13mA
2.775V    -255.4mA   -435.7mA   -105.5mA
2.83V     -346.8mA   -510.1mA   -140mA
2.885V    -443.7mA   -586mA     -224.2mA
2.94V     -544.2mA   -663.1mA   -343.4mA
2.995V    -647.3mA   -741.1mA   -478.8mA
3.05V     -752.2mA   -819.9mA   -622.5mA
3.6V      -1.846A    -1.632A    -2.185A
[Ramp]
| variable   typ   min   max
dV/dt_r   0.384/0.437n   0.249/0.502n   0.647/0.359n
dV/dt_f   0.492/0.449n   0.301/0.515n   0.721/0.363n
R_load = 50.000
[Rising Waveform]
R_fixture= 50.000
V_fixture= 0.0
V_fixture_min= 0.0
V_fixture_max= 0.0
|time   V(typ)   V(min)   V(max)
0s        8.268nV    71.3nV     4.54nV
701ps     -546.2uV   20.36uV    -18.87mV
911ps     -600uV     -4.009uV   581.9mV
1.105ns   -5.237mV   -481.8uV   835.3mV
1.328ns   -11.42mV   -215.5uV   946mV
1.681ns   419.5mV    -670.1uV   1.018V
2.053ns   556.1mV    -10.14mV   1.049V
3.003ns   621.3mV    334.7mV    1.074V
3.984ns   635.3mV    402.1mV    1.078V
20ns      640.6mV    415.2mV    1.079V
[Rising Waveform]
R_fixture= 50.000
V_fixture= 1.800
V_fixture_min= 1.710
V_fixture_max= 1.890
|time   V(typ)   V(min)   V(max)
0s        979.8mV    1.209V     687.7mV
624ps     979.5mV    1.209V     685.9mV
822ps     978.9mV    1.209V     1.54V
897ps     979.3mV    1.209V     1.708V
1.164ns   1.007V     1.208V     1.832V
1.482ns   1.621V     1.209V     1.863V
1.912ns   1.762V     1.194V     1.879V
2.469ns   1.782V     1.606V     1.887V
3.03ns    1.792V     1.691V     1.889V
20ns      1.8V       1.71V      1.89V
[Falling Waveform]
R_fixture= 50.000
V_fixture= 1.800
V_fixture_min= 1.710
V_fixture_max= 1.890
|time   V(typ)   V(min)   V(max)
0s        1.8V       1.71V      1.89V
729ps     1.799V     1.71V      1.921V
1.003ns   1.8V       1.71V      1.124V
1.372ns   1.832V     1.71V      824.7mV
1.696ns   1.32V      1.709V     750.4mV
2.068ns   1.103V     1.71V      714.8mV
2.499ns   1.037V     1.733V     698.9mV
3.201ns   1.004V     1.309V     690.2mV
4.296ns   986.1mV    1.229V     687.9mV
20ns      979.8mV    1.209V     687.7mV
[Falling Waveform]
R_fixture= 50.000
V_fixture= 0.0
V_fixture_min= 0.0
V_fixture_max= 0.0
|time   V(typ)   V(min)   V(max)
0s        640.6mV    415.2mV    1.079V
671ps     640.2mV    415.2mV    1.072V
891ps     640.2mV    415.1mV    198.1mV
1.231ns   637.4mV    414.9mV    28.4mV
1.334ns   527.5mV    415.1mV    20.51mV
1.606ns   94.68mV    415.3mV    11.02mV
2.123ns   12.65mV    419.5mV    3.061mV
2.767ns   4.947mV    60.19mV    761.5uV
3.39ns    1.809mV    8.434mV    204.6uV
20ns      -268.7nV   -28.66nV   -47.1nV
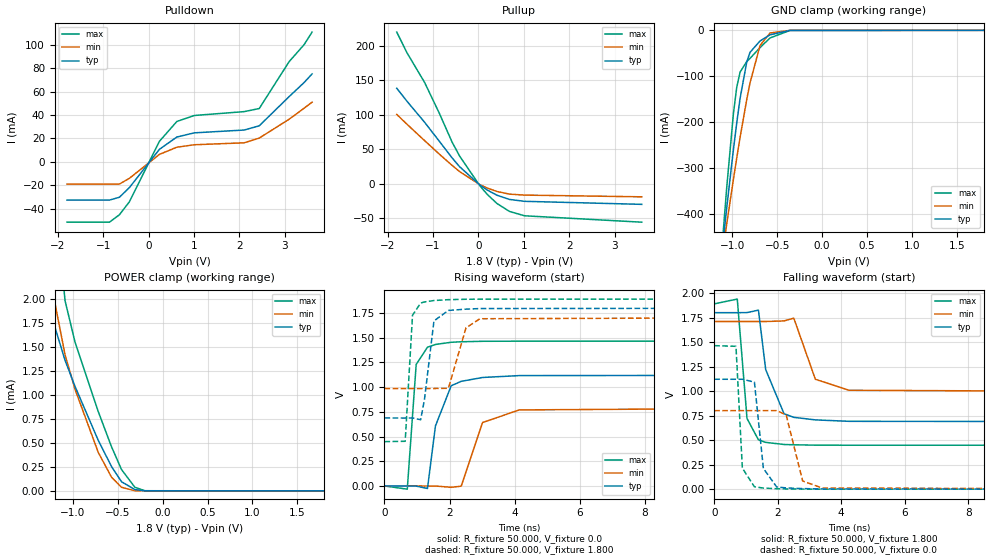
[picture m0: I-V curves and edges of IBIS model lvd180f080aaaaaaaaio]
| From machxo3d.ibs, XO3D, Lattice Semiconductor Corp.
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|   Model lvd180f080aaaaaaaaio
[Model] lvd180f080aaaaaaaaio
Model_type I/O
Polarity   Non-Inverting
Enable   Active-Low
Vinl =  0.630V
Vinh =  1.170V
Vmeas =  0.900V
Cref =  0.0F
Rref =  1.000M
Vref =  0.0V
C_comp   4.200pF   3.800pF   7.500pF
[Temperature Range]   25.000   0.105k   -40.000
[Voltage Range]   1.800V   1.710V   1.890V
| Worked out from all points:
|   slope of the pulldown table from 0 to 0.27 V, typ, clamps not added: 22.7 ohm
|   slope of the pullup table from 0 to 0.27 V, typ, clamps not added: 22.8 ohm
|   GND clamp passes 1 mA (typ) near -0.43 V on its own axis
|   POWER clamp passes 1 mA (typ) near -0.94 V on its own axis
|   rising waveform, R_fixture 50.000, V_fixture 0.0: 20-80 % time 347ps typ, 521ps min, 177ps max; typ from 0 V to 1.12 V
|   rising waveform, R_fixture 50.000, V_fixture 1.800: 20-80 % time 219ps typ, 376ps min, 113ps max; typ from 0.688 V to 1.8 V
|   falling waveform, R_fixture 50.000, V_fixture 1.800: 20-80 % time 364ps typ, 499ps min, 224ps max; typ from 1.8 V to 0.688 V
|   falling waveform, R_fixture 50.000, V_fixture 0.0: 20-80 % time 197ps typ, 327ps min, 118ps max; typ from 1.12 V to 0 V
[Pulldown]
|Voltage   I(typ)   I(min)   I(max)
-1.8V     -32.66mA   -18.98mA   -51.52mA
-865mV    -32.66mA   -18.98mA   -51.52mA
-645mV    -30.22mA   -18.98mA   -45.17mA
-425mV    -21.97mA   -14.07mA   -34.06mA
235mV     10.62mA    6.321mA    17.45mA
620mV     21.15mA    12.46mA    34.42mA
1.005V    24.72mA    14.56mA    39.54mA
2.105V    27.13mA    16.22mA    42.84mA
2.435V    30.72mA    20.25mA    45.46mA
3.095V    55.67mA    36.35mA    85.52mA
3.425V    67.68mA    45.78mA    100mA
3.6V      75.01mA    50.87mA    110.7mA
[Pullup]
|Voltage   I(typ)   I(min)   I(max)
-1.8V     138.2mA    100.4mA    219.4mA
-1.57V    119.1mA    85.94mA    189mA
-1.185V   88.96mA    62.47mA    146.5mA
-855mV    61.03mA    42.59mA    101.1mA
-580mV    37.52mA    26.75mA    60.33mA
-415mV    24.82mA    17.75mA    40.25mA
25mV      -1.264mA   -864.3uA   -2.139mA
190mV     -8.744mA   -5.939mA   -14.93mA
410mV     -16.44mA   -11.04mA   -28.45mA
685mV     -22.52mA   -14.83mA   -39.88mA
1.015V    -25.23mA   -16.24mA   -46.13mA
3.6V      -29.62mA   -18.73mA   -55.4mA
[GND_clamp]
|Voltage   I(typ)   I(min)   I(max)
-1.8V     -1.831A    -1.488A    -2.421A
-1.097V   -451mA     -469.7mA   -431.6mA
-1.06V    -384.8mA   -420mA     -340.3mA
-986mV    -258.9mA   -323.6mA   -180.7mA
-949mV    -200.9mA   -277.4mA   -123.7mA
-912mV    -148.2mA   -232.8mA   -90.76mA
-838mV    -69.05mA   -150.6mA   -67.91mA
-801mV    -47.74mA   -114.1mA   -60.88mA
-690mV    -23.16mA   -33.02mA   -37.51mA
-579mV    -9.79mA    -5.846mA   -16.62mA
-357mV    -148.7uA   -66.38uA   -242.3uA
1.8V      0A         0A         0A
[POWER_clamp]
|Voltage   I(typ)   I(min)   I(max)
-1.8V     9.805mA    6.292mA    21.89mA
-1.271V   2.077mA    2.399mA    4.682mA
-1.234V   1.861mA    2.168mA    3.79mA
-1.197V   1.7mA      1.95mA     3.092mA
-1.086V   1.36mA     1.418mA    1.981mA
-975mV    1.088mA    1.058mA    1.55mA
-716mV    526uA      400.6uA    825.4uA
-568mV    252.9uA    142.1uA    458.4uA
-457mV    95.28uA    37.76uA    222.2uA
-309mV    14.3uA     2.005uA    38.47uA
-198mV    1.727uA    1.797uA    2.013uA
1.8V      0A         0A         4.279nA
[Ramp]
| variable   typ   min   max
dV/dt_r   0.673/0.354n   0.481/0.518n   0.878/0.177n
dV/dt_f   0.667/0.366n   0.435/0.484n   0.865/0.225n
R_load = 50.000
[Rising Waveform]
R_fixture= 50.000
V_fixture= 0.0
V_fixture_min= 0.0
V_fixture_max= 0.0
|time   V(typ)   V(min)   V(max)
0s        6.274nV    56.81nV    3.312nV
700ps     -476.6uV   14.97uV    -32.45mV
974ps     -1.534mV   -119.9uV   1.229V
1.321ns   -25.47mV   -283.4uV   1.403V
1.566ns   607mV      -447.4uV   1.431V
2.049ns   1.013V     -13.85mV   1.453V
2.357ns   1.058V     -1.74mV    1.458V
3.013ns   1.097V     641.3mV    1.463V
4.141ns   1.116V     769mV      1.464V
20ns      1.121V     801mV      1.464V
[Rising Waveform]
R_fixture= 50.000
V_fixture= 1.800
V_fixture_min= 1.710
V_fixture_max= 1.890
|time   V(typ)   V(min)   V(max)
0s        687.7mV    984.9mV    448.1mV
636ps     686.9mV    984.9mV    451.8mV
861ps     687.3mV    984.9mV    1.726V
1.111ns   669.7mV    984mV      1.85V
1.23ns    878mV      983.9mV    1.861V
1.52ns    1.669V     985.6mV    1.875V
1.965ns   1.775V     987.8mV    1.884V
2.505ns   1.788V     1.599V     1.888V
2.931ns   1.794V     1.691V     1.889V
20ns      1.8V       1.71V      1.89V
[Falling Waveform]
R_fixture= 50.000
V_fixture= 1.800
V_fixture_min= 1.710
V_fixture_max= 1.890
|time   V(typ)   V(min)   V(max)
0s        1.8V       1.71V      1.89V
727ps     1.8V       1.71V      1.939V
1.034ns   1.801V     1.71V      720.6mV
1.394ns   1.826V     1.71V      503.2mV
1.622ns   1.22V      1.71V      477.4mV
2.199ns   769.3mV    1.716V     455.7mV
2.508ns   732.5mV    1.744V     452.7mV
3.186ns   706.7mV    1.121V     448.9mV
4.245ns   692mV      1.009V     448.1mV
20ns      687.6mV    984.9mV    448mV
[Falling Waveform]
R_fixture= 50.000
V_fixture= 0.0
V_fixture_min= 0.0
V_fixture_max= 0.0
|time   V(typ)   V(min)   V(max)
0s        1.121V     801mV      1.464V
686ps     1.121V     801mV      1.457V
887ps     1.121V     800.8mV    214.2mV
1.267ns   1.092V     801.1mV    24.22mV
1.549ns   211.9mV    801.4mV    11.37mV
1.968ns   22.69mV    801.5mV    4.351mV
2.267ns   12.83mV    757.1mV    2.289mV
2.786ns   5.724mV    83.78mV    726.5uV
3.403ns   2.391mV    11.24mV    186.3uV
20ns      -186.7nV   -26.82nV   -1.189nV
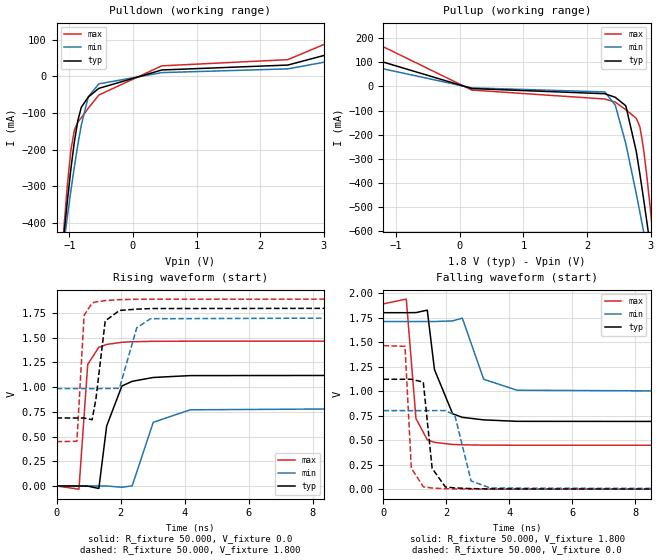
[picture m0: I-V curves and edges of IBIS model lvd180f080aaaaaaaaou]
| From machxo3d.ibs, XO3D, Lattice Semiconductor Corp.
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|   Model lvd180f080aaaaaaaaou
[Model] lvd180f080aaaaaaaaou
Model_type Output
Polarity   Non-Inverting
Enable   Active-High
Vmeas =  0.900V
Cref =  0.0F
Rref =  1.000M
Vref =  0.0V
C_comp   4.200pF   3.800pF   7.500pF
[Temperature Range]   25.000   0.105k   -40.000
[Voltage Range]   1.800V   1.710V   1.890V
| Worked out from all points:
|   slope of the pulldown table from 0 to 0.27 V, typ, clamps not added: 22.7 ohm
|   slope of the pullup table from 0 to 0.27 V, typ, clamps not added: 22.8 ohm
|   rising waveform, R_fixture 50.000, V_fixture 0.0: 20-80 % time 347ps typ, 522ps min, 177ps max; typ from 0 V to 1.12 V
|   rising waveform, R_fixture 50.000, V_fixture 1.800: 20-80 % time 219ps typ, 376ps min, 113ps max; typ from 0.688 V to 1.8 V
|   falling waveform, R_fixture 50.000, V_fixture 1.800: 20-80 % time 364ps typ, 499ps min, 224ps max; typ from 1.8 V to 0.688 V
|   falling waveform, R_fixture 50.000, V_fixture 0.0: 20-80 % time 197ps typ, 327ps min, 118ps max; typ from 1.12 V to 0 V
[Pulldown]
|Voltage   I(typ)   I(min)   I(max)
-1.8V     -1.832A    -1.489A    -2.422A
-1.085V   -435.6mA   -456.5mA   -416.8mA
-1.03V    -341.1mA   -383.9mA   -297.5mA
-975mV    -254mA     -314mA     -203.2mA
-920mV    -179mA     -247.8mA   -146.5mA
-865mV    -120.6mA   -186.7mA   -125mA
-810mV    -84.09mA   -132.7mA   -112.7mA
-700mV    -56.23mA   -55.37mA   -86.55mA
-535mV    -32.62mA   -20.37mA   -50.81mA
455mV     17.66mA    10.44mA    28.95mA
2.435V    31.09mA    20.67mA    45.87mA
3.6V      84.82mA    57.89mA    130.9mA
[Pullup]
|Voltage   I(typ)   I(min)   I(max)
-1.8V     148mA      106.7mA    241.3mA
190mV     -8.744mA   -5.939mA   -14.93mA
2.28V     -30.13mA   -22.66mA   -52mA
2.445V    -45.05mA   -77.36mA   -64.91mA
2.61V     -80mA      -236.8mA   -96.38mA
2.775V    -269.7mA   -444.8mA   -132mA
2.83V     -361mA     -519.2mA   -166.6mA
2.885V    -458mA     -595.1mA   -250.9mA
2.94V     -558.6mA   -672.2mA   -370.1mA
2.995V    -661.7mA   -750.3mA   -505.6mA
3.05V     -766.6mA   -829.1mA   -649.4mA
3.6V      -1.86A     -1.641A    -2.213A
[Ramp]
| variable   typ   min   max
dV/dt_r   0.673/0.354n   0.481/0.518n   0.878/0.177n
dV/dt_f   0.667/0.366n   0.435/0.484n   0.865/0.225n
R_load = 50.000
[Rising Waveform]
R_fixture= 50.000
V_fixture= 0.0
V_fixture_min= 0.0
V_fixture_max= 0.0
|time   V(typ)   V(min)   V(max)
0s        6.274nV    56.81nV    3.312nV
700ps     -476.6uV   14.97uV    -32.45mV
974ps     -1.534mV   -119.9uV   1.229V
1.321ns   -25.47mV   -283.4uV   1.403V
1.566ns   607mV      -447.5uV   1.431V
2.041ns   1.011V     -13.13mV   1.453V
2.361ns   1.058V     1.229mV    1.458V
3.02ns    1.097V     643.7mV    1.463V
4.172ns   1.116V     770mV      1.464V
20ns      1.121V     801mV      1.464V
[Rising Waveform]
R_fixture= 50.000
V_fixture= 1.800
V_fixture_min= 1.710
V_fixture_max= 1.890
|time   V(typ)   V(min)   V(max)
0s        687.7mV    984.9mV    448.1mV
636ps     686.9mV    984.9mV    451.8mV
861ps     687.3mV    984.9mV    1.726V
1.111ns   669.7mV    984mV      1.85V
1.23ns    878mV      983.9mV    1.861V
1.52ns    1.669V     985.6mV    1.875V
1.965ns   1.775V     987.8mV    1.884V
2.505ns   1.788V     1.599V     1.888V
2.931ns   1.794V     1.691V     1.889V
20ns      1.8V       1.71V      1.89V
[Falling Waveform]
R_fixture= 50.000
V_fixture= 1.800
V_fixture_min= 1.710
V_fixture_max= 1.890
|time   V(typ)   V(min)   V(max)
0s        1.8V       1.71V      1.89V
727ps     1.8V       1.71V      1.939V
1.034ns   1.801V     1.71V      720.6mV
1.394ns   1.826V     1.71V      503.2mV
1.622ns   1.22V      1.71V      477.4mV
2.199ns   769.3mV    1.716V     455.7mV
2.508ns   732.5mV    1.744V     452.7mV
3.186ns   706.7mV    1.121V     448.9mV
4.245ns   692mV      1.009V     448.1mV
20ns      687.6mV    984.9mV    448mV
[Falling Waveform]
R_fixture= 50.000
V_fixture= 0.0
V_fixture_min= 0.0
V_fixture_max= 0.0
|time   V(typ)   V(min)   V(max)
0s        1.121V     801mV      1.464V
686ps     1.121V     801mV      1.457V
887ps     1.121V     800.8mV    214.2mV
1.267ns   1.092V     801.1mV    24.22mV
1.549ns   211.9mV    801.4mV    11.37mV
1.968ns   22.69mV    801.5mV    4.351mV
2.267ns   12.83mV    757.1mV    2.289mV
2.786ns   5.724mV    83.78mV    726.5uV
3.403ns   2.391mV    11.24mV    186.3uV
20ns      -186.7nV   -26.82nV   -1.189nV
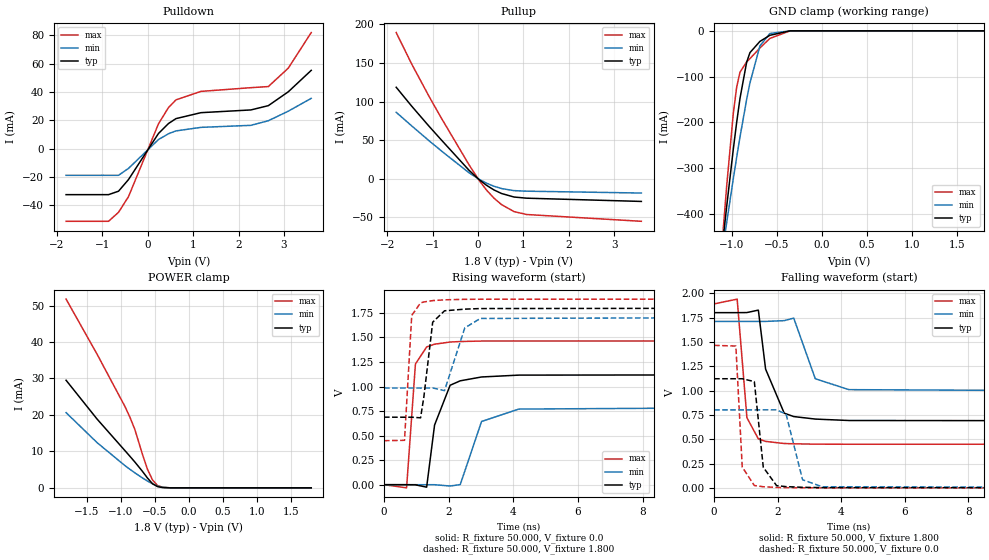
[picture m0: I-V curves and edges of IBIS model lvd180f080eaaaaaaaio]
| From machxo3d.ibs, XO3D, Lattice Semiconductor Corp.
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|   Model lvd180f080eaaaaaaaio
[Model] lvd180f080eaaaaaaaio
Model_type I/O
Polarity   Non-Inverting
Enable   Active-Low
Vinl =  0.630V
Vinh =  1.170V
Vmeas =  0.900V
Cref =  0.0F
Rref =  1.000M
Vref =  0.0V
C_comp   4.200pF   3.800pF   7.500pF
[Temperature Range]   25.000   0.105k   -40.000
[Voltage Range]   1.800V   1.710V   1.890V
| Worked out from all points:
|   slope of the pulldown table from 0 to 0.27 V, typ, clamps not added: 22.7 ohm
|   slope of the pullup table from 0 to 0.27 V, typ, clamps not added: 22.8 ohm
|   GND clamp passes 1 mA (typ) near -0.43 V on its own axis
|   POWER clamp passes 1 mA (typ) near -0.52 V on its own axis
|   rising waveform, R_fixture 50.000, V_fixture 0.0: 20-80 % time 348ps typ, 522ps min, 177ps max; typ from 0 V to 1.12 V
|   rising waveform, R_fixture 50.000, V_fixture 1.800: 20-80 % time 219ps typ, 376ps min, 114ps max; typ from 0.688 V to 1.8 V
|   falling waveform, R_fixture 50.000, V_fixture 1.800: 20-80 % time 364ps typ, 499ps min, 224ps max; typ from 1.8 V to 0.688 V
|   falling waveform, R_fixture 50.000, V_fixture 0.0: 20-80 % time 197ps typ, 327ps min, 118ps max; typ from 1.12 V to 0 V
[Pulldown]
|Voltage   I(typ)   I(min)   I(max)
-1.8V     -32.66mA   -18.98mA   -51.52mA
-865mV    -32.66mA   -18.98mA   -51.52mA
-645mV    -30.22mA   -18.98mA   -45.17mA
-425mV    -21.97mA   -14.07mA   -34.06mA
235mV     10.62mA    6.321mA    17.45mA
455mV     17.66mA    10.44mA    28.95mA
620mV     21.15mA    12.46mA    34.42mA
1.17V     25.36mA    14.95mA    40.42mA
2.27V     27.29mA    16.39mA    43.05mA
2.655V    30.33mA    19.65mA    43.83mA
3.095V    40.15mA    26.43mA    56.91mA
3.6V      55.31mA    35.5mA     82.05mA
[Pullup]
|Voltage   I(typ)   I(min)   I(max)
-1.8V     118.5mA    86.03mA    189.5mA
-1.46V    94.07mA    68.47mA    148.8mA
-1.075V   67.82mA    49.06mA    106.5mA
-800mV    49.79mA    35.7mA     77.95mA
-195mV    10.76mA    7.525mA    17.82mA
25mV      -1.264mA   -864.3uA   -2.139mA
190mV     -8.744mA   -5.939mA   -14.93mA
355mV     -14.76mA   -9.939mA   -25.44mA
520mV     -19.33mA   -12.89mA   -33.74mA
795mV     -23.9mA    -15.59mA   -42.8mA
1.07V     -25.4mA    -16.32mA   -46.58mA
3.6V      -29.62mA   -18.73mA   -55.4mA
[GND_clamp]
|Voltage   I(typ)   I(min)   I(max)
-1.8V     -1.831A    -1.488A    -2.421A
-1.097V   -451mA     -469.7mA   -431.6mA
-1.06V    -384.8mA   -420mA     -340.3mA
-986mV    -258.9mA   -323.6mA   -180.7mA
-949mV    -200.9mA   -277.4mA   -123.7mA
-912mV    -148.2mA   -232.8mA   -90.76mA
-838mV    -69.05mA   -150.6mA   -67.91mA
-801mV    -47.74mA   -114.1mA   -60.88mA
-690mV    -23.16mA   -33.02mA   -37.51mA
-579mV    -9.79mA    -5.846mA   -16.62mA
-357mV    -148.7uA   -66.38uA   -242.3uA
1.8V      0A         0A         0A
[POWER_clamp]
|Voltage   I(typ)   I(min)   I(max)
-1.8V     29.51mA    20.63mA    51.76mA
-1.345V   18.87mA    12.41mA    36.66mA
-938mV    10.26mA    6.136mA    22.4mA
-864mV    8.689mA    5.106mA    19.43mA
-790mV    7.087mA    4.117mA    16.01mA
-679mV    4.54mA     2.724mA    9.207mA
-605mV    2.701mA    1.871mA    5.102mA
-531mV    1.131mA    1.1mA      2.169mA
-457mV    338.1uA    470.7uA    629.2uA
-383mV    89.2uA     117.2uA    163.1uA
-272mV    9.185uA    9.485uA    15.7uA
1.8V      0A         0A         4.279nA
[Ramp]
| variable   typ   min   max
dV/dt_r   0.673/0.354n   0.481/0.518n   0.878/0.177n
dV/dt_f   0.667/0.366n   0.435/0.484n   0.865/0.225n
R_load = 50.000
[Rising Waveform]
R_fixture= 50.000
V_fixture= 0.0
V_fixture_min= 0.0
V_fixture_max= 0.0
|time   V(typ)   V(min)   V(max)
0s        6.274nV    56.81nV    3.312nV
700ps     -476.6uV   15.14uV    -32.45mV
974ps     -1.534mV   -119.9uV   1.229V
1.321ns   -25.47mV   -283.4uV   1.403V
1.566ns   607mV      -458.3uV   1.431V
2.048ns   1.013V     -13.69mV   1.453V
2.361ns   1.058V     1.229mV    1.458V
3.02ns    1.097V     643.7mV    1.463V
4.172ns   1.116V     770mV      1.464V
20ns      1.121V     801mV      1.464V
[Rising Waveform]
R_fixture= 50.000
V_fixture= 1.800
V_fixture_min= 1.710
V_fixture_max= 1.890
|time   V(typ)   V(min)   V(max)
0s        687.7mV    984.9mV    448.1mV
636ps     686.9mV    984.9mV    451.7mV
860ps     687.3mV    984.9mV    1.724V
1.133ns   681mV      984mV      1.852V
1.236ns   896.8mV    983.9mV    1.861V
1.508ns   1.655V     985.6mV    1.875V
1.874ns   1.771V     957.9mV    1.883V
2.501ns   1.788V     1.597V     1.888V
2.981ns   1.794V     1.693V     1.889V
20ns      1.8V       1.71V      1.89V
[Falling Waveform]
R_fixture= 50.000
V_fixture= 1.800
V_fixture_min= 1.710
V_fixture_max= 1.890
|time   V(typ)   V(min)   V(max)
0s        1.8V       1.71V      1.89V
727ps     1.8V       1.71V      1.939V
1.034ns   1.801V     1.71V      720.6mV
1.394ns   1.826V     1.71V      503.2mV
1.622ns   1.22V      1.71V      477.4mV
2.208ns   767.5mV    1.718V     455.7mV
2.508ns   732.5mV    1.744V     452.7mV
3.186ns   706.7mV    1.121V     448.9mV
4.245ns   692mV      1.009V     448.1mV
20ns      687.6mV    984.9mV    448mV
[Falling Waveform]
R_fixture= 50.000
V_fixture= 0.0
V_fixture_min= 0.0
V_fixture_max= 0.0
|time   V(typ)   V(min)   V(max)
0s        1.121V     801mV      1.464V
686ps     1.121V     801mV      1.457V
887ps     1.121V     800.8mV    214.2mV
1.267ns   1.092V     801.1mV    24.22mV
1.549ns   211.9mV    801.4mV    11.37mV
1.968ns   22.69mV    801.5mV    4.351mV
2.267ns   12.83mV    757.1mV    2.289mV
2.786ns   5.724mV    83.78mV    726.5uV
3.403ns   2.391mV    11.24mV    186.3uV
20ns      -186.7nV   -26.82nV   -1.189nV
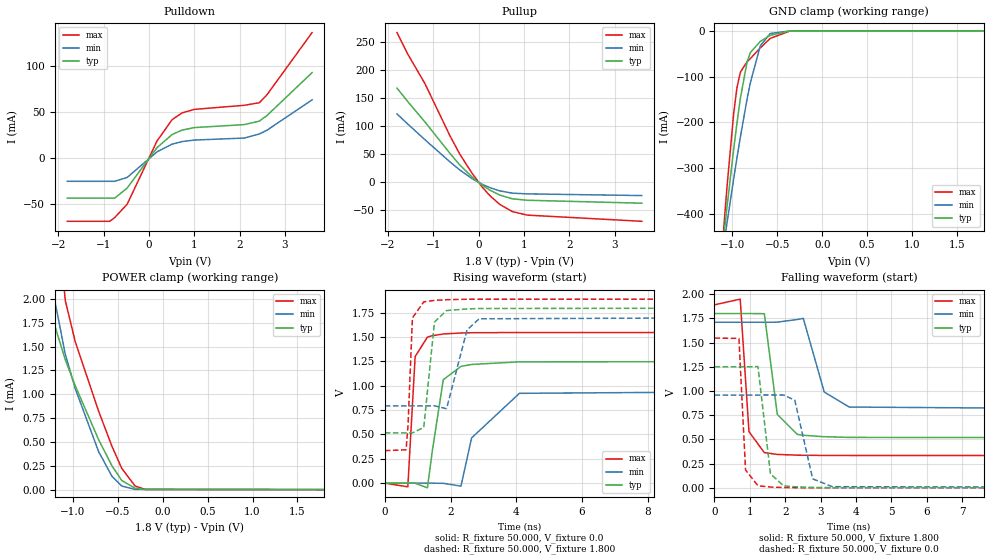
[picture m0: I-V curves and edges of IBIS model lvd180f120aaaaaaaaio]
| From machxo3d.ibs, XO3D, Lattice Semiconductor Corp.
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|   Model lvd180f120aaaaaaaaio
[Model] lvd180f120aaaaaaaaio
Model_type I/O
Polarity   Non-Inverting
Enable   Active-Low
Vinl =  0.630V
Vinh =  1.170V
Vmeas =  0.900V
Cref =  0.0F
Rref =  1.000M
Vref =  0.0V
C_comp   4.200pF   3.800pF   7.500pF
[Temperature Range]   25.000   0.105k   -40.000
[Voltage Range]   1.800V   1.710V   1.890V
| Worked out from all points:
|   slope of the pulldown table from 0 to 0.27 V, typ, clamps not added: 17 ohm
|   slope of the pullup table from 0 to 0.27 V, typ, clamps not added: 18.2 ohm
|   GND clamp passes 1 mA (typ) near -0.43 V on its own axis
|   POWER clamp passes 1 mA (typ) near -0.94 V on its own axis
|   rising waveform, R_fixture 50.000, V_fixture 0.0: 20-80 % time 298ps typ, 495ps min, 139ps max; typ from 0 V to 1.25 V
|   rising waveform, R_fixture 50.000, V_fixture 1.800: 20-80 % time 204ps typ, 362ps min, 99.2ps max; typ from 0.517 V to 1.8 V
|   falling waveform, R_fixture 50.000, V_fixture 1.800: 20-80 % time 283ps typ, 448ps min, 159ps max; typ from 1.8 V to 0.517 V
|   falling waveform, R_fixture 50.000, V_fixture 0.0: 20-80 % time 179ps typ, 317ps min, 99.2ps max; typ from 1.25 V to 0 V
[Pulldown]
|Voltage   I(typ)   I(min)   I(max)
-1.8V     -43.55mA   -25.31mA   -68.69mA
-865mV    -43.55mA   -25.31mA   -68.69mA
-755mV    -43.55mA   -25.31mA   -64.67mA
-480mV    -32.67mA   -21.16mA   -50.21mA
180mV     11.24mA    6.697mA    18.47mA
510mV     25.33mA    14.95mA    41.43mA
730mV     30.23mA    17.79mA    48.88mA
1.005V    32.96mA    19.42mA    52.72mA
2.105V    36.18mA    21.59mA    57.12mA
2.435V    39.95mA    26.03mA    59.92mA
2.6V      45.84mA    29.94mA    68.24mA
3.6V      92.54mA    63.01mA    136mA
[Pullup]
|Voltage   I(typ)   I(min)   I(max)
-1.8V     167.9mA    121.9mA    266.9mA
-1.57V    144.6mA    104.5mA    229.5mA
-1.185V   107.8mA    76.11mA    176.1mA
-635mV    52.07mA    36.82mA    83.5mA
-415mV    31mA       22.14mA    50.28mA
-140mV    9.467mA    6.582mA    15.76mA
80mV      -4.903mA   -3.346mA   -8.323mA
245mV     -13.64mA   -9.238mA   -23.35mA
465mV     -22.46mA   -15.03mA   -39.02mA
740mV     -29.1mA    -19.08mA   -51.81mA
1.07V     -31.75mA   -20.4mA    -58.22mA
3.6V      -37.02mA   -23.41mA   -69.25mA
[GND_clamp]
|Voltage   I(typ)   I(min)   I(max)
-1.8V     -1.831A    -1.488A    -2.421A
-1.097V   -451mA     -469.7mA   -431.6mA
-1.06V    -384.8mA   -420mA     -340.3mA
-986mV    -258.9mA   -323.6mA   -180.7mA
-949mV    -200.9mA   -277.4mA   -123.7mA
-912mV    -148.2mA   -232.8mA   -90.76mA
-838mV    -69.05mA   -150.6mA   -67.91mA
-801mV    -47.74mA   -114.1mA   -60.88mA
-690mV    -23.16mA   -33.02mA   -37.51mA
-579mV    -9.79mA    -5.846mA   -16.62mA
-357mV    -148.7uA   -66.38uA   -242.3uA
1.8V      0A         0A         0A
[POWER_clamp]
|Voltage   I(typ)   I(min)   I(max)
-1.8V     9.805mA    6.292mA    21.89mA
-1.271V   2.077mA    2.399mA    4.682mA
-1.234V   1.861mA    2.168mA    3.79mA
-1.197V   1.7mA      1.95mA     3.092mA
-1.086V   1.36mA     1.418mA    1.981mA
-975mV    1.088mA    1.058mA    1.55mA
-716mV    526uA      400.6uA    825.4uA
-568mV    252.9uA    142.1uA    458.4uA
-457mV    95.28uA    37.76uA    222.2uA
-309mV    14.3uA     2.005uA    38.47uA
-198mV    1.727uA    1.797uA    2.013uA
1.8V      0A         0A         4.279nA
[Ramp]
| variable   typ   min   max
dV/dt_r   0.750/0.293n   0.575/0.492n   0.928/0.139n
dV/dt_f   0.770/0.278n   0.550/0.451n   0.933/0.159n
R_load = 50.000
[Rising Waveform]
R_fixture= 50.000
V_fixture= 0.0
V_fixture_min= 0.0
V_fixture_max= 0.0
|time   V(typ)   V(min)   V(max)
0s        5.055nV    47.21nV    2.607nV
701ps     -401.1uV   9.996uV    -37.65mV
924ps     -998.2uV   -13.51uV   1.3V
1.297ns   -48.42mV   -224.4uV   1.5V
1.443ns   322.8mV    -16.54uV   1.514V
1.779ns   1.062V     -1.872mV   1.532V
2.317ns   1.199V     -30.68mV   1.542V
2.642ns   1.219V     464.6mV    1.545V
4.096ns   1.246V     922.5mV    1.547V
20ns      1.25V      958.6mV    1.547V
[Rising Waveform]
R_fixture= 50.000
V_fixture= 1.800
V_fixture_min= 1.710
V_fixture_max= 1.890
|time   V(typ)   V(min)   V(max)
0s        516.8mV    793.5mV    334.2mV
647ps     516.1mV    793.5mV    342.1mV
706ps     516mV      793.5mV    581.8mV
841ps     516.5mV    793.5mV    1.697V
1.186ns   571.9mV    792.6mV    1.862V
1.511ns   1.654V     794.2mV    1.877V
1.879ns   1.773V     764.9mV    1.884V
2.503ns   1.789V     1.574V     1.889V
2.871ns   1.794V     1.688V     1.889V
20ns      1.8V       1.71V      1.89V
[Falling Waveform]
R_fixture= 50.000
V_fixture= 1.800
V_fixture_min= 1.710
V_fixture_max= 1.890
|time   V(typ)   V(min)   V(max)
0s        1.8V       1.71V      1.89V
727ps     1.8V       1.71V      1.949V
975ps     1.8V       1.71V      580.4mV
1.409ns   1.799V     1.71V      363.6mV
1.775ns   759.2mV    1.711V     345.6mV
2.343ns   551.9mV    1.739V     337.5mV
2.511ns   543mV      1.75V      336.4mV
3.102ns   528.4mV    990.3mV    334.8mV
3.806ns   521mV      834.6mV    334.3mV
20ns      516.8mV    793.5mV    334.2mV
[Falling Waveform]
R_fixture= 50.000
V_fixture= 0.0
V_fixture_min= 0.0
V_fixture_max= 0.0
|time   V(typ)   V(min)   V(max)
0s        1.25V      958.6mV    1.547V
691ps     1.25V      958.6mV    1.543V
878ps     1.25V      958.4mV    184.6mV
1.229ns   1.252V     958.5mV    21.69mV
1.582ns   144.3mV    959mV      8.646mV
1.955ns   20.34mV    958.7mV    3.513mV
2.271ns   11.13mV    905.1mV    1.684mV
2.775ns   4.978mV    93.12mV    548.4uV
3.331ns   2.305mV    12.35mV    179.6uV
20ns      -197nV     26.69nV    -204.9nV
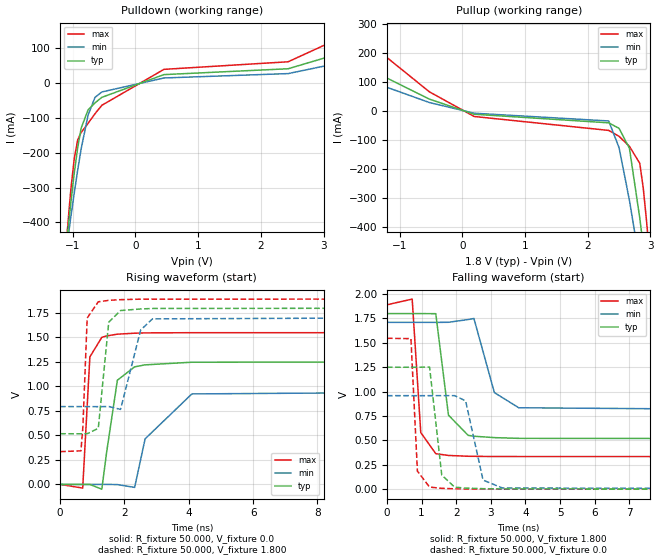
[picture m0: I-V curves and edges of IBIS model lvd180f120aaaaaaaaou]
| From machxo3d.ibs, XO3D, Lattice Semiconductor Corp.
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|   Model lvd180f120aaaaaaaaou
[Model] lvd180f120aaaaaaaaou
Model_type Output
Polarity   Non-Inverting
Enable   Active-High
Vmeas =  0.900V
Cref =  0.0F
Rref =  1.000M
Vref =  0.0V
C_comp   4.200pF   3.800pF   7.500pF
[Temperature Range]   25.000   0.105k   -40.000
[Voltage Range]   1.800V   1.710V   1.890V
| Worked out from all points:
|   slope of the pulldown table from 0 to 0.27 V, typ, clamps not added: 17 ohm
|   slope of the pullup table from 0 to 0.27 V, typ, clamps not added: 18.2 ohm
|   rising waveform, R_fixture 50.000, V_fixture 0.0: 20-80 % time 298ps typ, 495ps min, 139ps max; typ from 0 V to 1.25 V
|   rising waveform, R_fixture 50.000, V_fixture 1.800: 20-80 % time 204ps typ, 362ps min, 99.2ps max; typ from 0.517 V to 1.8 V
|   falling waveform, R_fixture 50.000, V_fixture 1.800: 20-80 % time 283ps typ, 448ps min, 159ps max; typ from 1.8 V to 0.517 V
|   falling waveform, R_fixture 50.000, V_fixture 0.0: 20-80 % time 179ps typ, 317ps min, 99.2ps max; typ from 1.25 V to 0 V
[Pulldown]
|Voltage   I(typ)   I(min)   I(max)
-1.8V     -1.833A    -1.489A    -2.423A
-1.085V   -437.7mA   -457.5mA   -421.9mA
-1.03V    -344mA     -385.1mA   -306.4mA
-975mV    -258.3mA   -315.5mA   -217.1mA
-920mV    -185.6mA   -249.6mA   -163.3mA
-865mV    -129.9mA   -189.1mA   -142.2mA
-755mV    -77.61mA   -92.79mA   -116.1mA
-645mV    -57.48mA   -41.86mA   -88.65mA
-535mV    -41.53mA   -26.19mA   -64.36mA
455mV     23.55mA    13.92mA    38.6mA
2.435V    40.32mA    26.45mA    60.32mA
3.6V      102.3mA    70.03mA    156.2mA
[Pullup]
|Voltage   I(typ)   I(min)   I(max)
-1.8V     177.7mA    128.2mA    288.8mA
-525mV    41.18mA    29.45mA    66.36mA
190mV     -10.93mA   -7.424mA   -18.66mA
2.335V    -40.52mA   -34.1mA    -66.62mA
2.5V      -59.56mA   -126.3mA   -87.07mA
2.665V    -128.1mA   -307.3mA   -121.5mA
2.83V     -368.2mA   -523.7mA   -179.9mA
2.885V    -465.2mA   -599.6mA   -264.3mA
2.94V     -565.8mA   -676.7mA   -383.5mA
2.995V    -668.9mA   -754.8mA   -519mA
3.05V     -773.9mA   -833.7mA   -662.9mA
3.6V      -1.868A    -1.646A    -2.227A
[Ramp]
| variable   typ   min   max
dV/dt_r   0.750/0.293n   0.575/0.492n   0.928/0.139n
dV/dt_f   0.770/0.278n   0.550/0.451n   0.933/0.159n
R_load = 50.000
[Rising Waveform]
R_fixture= 50.000
V_fixture= 0.0
V_fixture_min= 0.0
V_fixture_max= 0.0
|time   V(typ)   V(min)   V(max)
0s        5.055nV    47.21nV    2.607nV
701ps     -401.1uV   9.997uV    -37.65mV
924ps     -998.2uV   -13.51uV   1.3V
1.296ns   -48.66mV   -224.4uV   1.5V
1.443ns   322.8mV    -16.54uV   1.514V
1.779ns   1.062V     -1.872mV   1.532V
2.317ns   1.199V     -30.68mV   1.542V
2.642ns   1.219V     464.6mV    1.545V
4.096ns   1.246V     922.5mV    1.547V
20ns      1.25V      958.6mV    1.547V
[Rising Waveform]
R_fixture= 50.000
V_fixture= 1.800
V_fixture_min= 1.710
V_fixture_max= 1.890
|time   V(typ)   V(min)   V(max)
0s        516.8mV    793.5mV    334.2mV
647ps     516.1mV    793.5mV    342.1mV
706ps     516mV      793.5mV    581.8mV
841ps     516.5mV    793.5mV    1.697V
1.186ns   571.9mV    792.6mV    1.862V
1.511ns   1.654V     794.2mV    1.877V
1.879ns   1.773V     764.9mV    1.884V
2.503ns   1.789V     1.574V     1.889V
2.871ns   1.794V     1.688V     1.889V
20ns      1.8V       1.71V      1.89V
[Falling Waveform]
R_fixture= 50.000
V_fixture= 1.800
V_fixture_min= 1.710
V_fixture_max= 1.890
|time   V(typ)   V(min)   V(max)
0s        1.8V       1.71V      1.89V
727ps     1.8V       1.71V      1.949V
975ps     1.8V       1.71V      580.4mV
1.409ns   1.799V     1.71V      363.6mV
1.775ns   759.2mV    1.711V     345.6mV
2.343ns   551.9mV    1.739V     337.5mV
2.511ns   543mV      1.75V      336.5mV
3.102ns   528.4mV    990.3mV    334.8mV
3.806ns   521mV      834.6mV    334.3mV
20ns      516.8mV    793.5mV    334.2mV
[Falling Waveform]
R_fixture= 50.000
V_fixture= 0.0
V_fixture_min= 0.0
V_fixture_max= 0.0
|time   V(typ)   V(min)   V(max)
0s        1.25V      958.6mV    1.547V
691ps     1.25V      958.6mV    1.543V
878ps     1.25V      958.4mV    184.6mV
1.229ns   1.252V     958.5mV    21.69mV
1.582ns   144.3mV    959mV      8.646mV
1.955ns   20.34mV    958.7mV    3.513mV
2.271ns   11.13mV    905.1mV    1.684mV
2.775ns   4.978mV    93.12mV    548.4uV
3.331ns   2.305mV    12.35mV    179.6uV
20ns      -197nV     26.69nV    -204.9nV
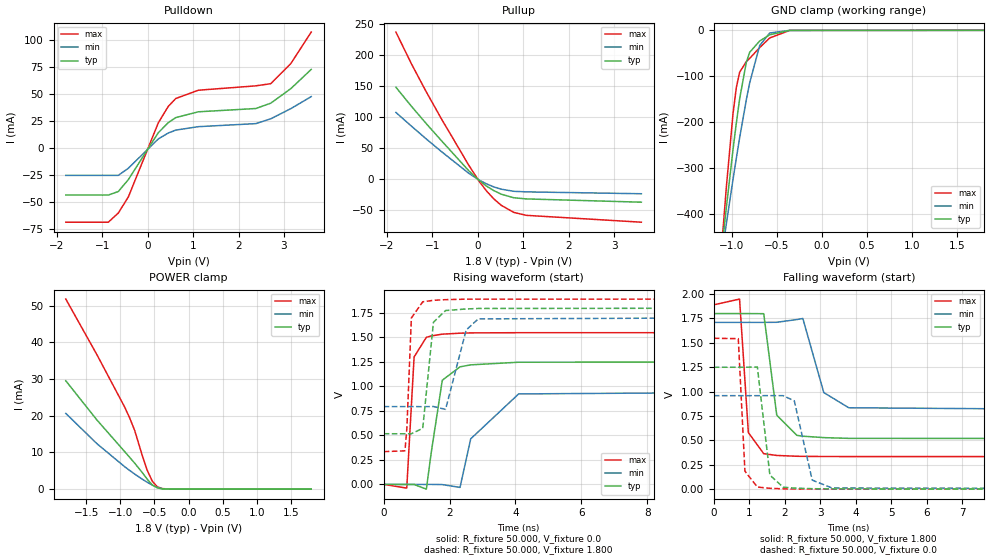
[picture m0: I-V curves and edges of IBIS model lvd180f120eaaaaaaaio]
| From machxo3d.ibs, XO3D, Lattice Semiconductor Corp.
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|   Model lvd180f120eaaaaaaaio
[Model] lvd180f120eaaaaaaaio
Model_type I/O
Polarity   Non-Inverting
Enable   Active-Low
Vinl =  0.630V
Vinh =  1.170V
Vmeas =  0.900V
Cref =  0.0F
Rref =  1.000M
Vref =  0.0V
C_comp   4.200pF   3.800pF   7.500pF
[Temperature Range]   25.000   0.105k   -40.000
[Voltage Range]   1.800V   1.710V   1.890V
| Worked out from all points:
|   slope of the pulldown table from 0 to 0.27 V, typ, clamps not added: 17 ohm
|   slope of the pullup table from 0 to 0.27 V, typ, clamps not added: 18.2 ohm
|   GND clamp passes 1 mA (typ) near -0.43 V on its own axis
|   POWER clamp passes 1 mA (typ) near -0.52 V on its own axis
|   rising waveform, R_fixture 50.000, V_fixture 0.0: 20-80 % time 298ps typ, 495ps min, 139ps max; typ from 0 V to 1.25 V
|   rising waveform, R_fixture 50.000, V_fixture 1.800: 20-80 % time 204ps typ, 362ps min, 99.2ps max; typ from 0.517 V to 1.8 V
|   falling waveform, R_fixture 50.000, V_fixture 1.800: 20-80 % time 283ps typ, 448ps min, 158ps max; typ from 1.8 V to 0.517 V
|   falling waveform, R_fixture 50.000, V_fixture 0.0: 20-80 % time 179ps typ, 317ps min, 99.2ps max; typ from 1.25 V to 0 V
[Pulldown]
|Voltage   I(typ)   I(min)   I(max)
-1.8V     -43.55mA   -25.31mA   -68.69mA
-865mV    -43.55mA   -25.31mA   -68.69mA
-645mV    -40.3mA    -25.31mA   -60.23mA
-425mV    -29.3mA    -18.76mA   -45.41mA
235mV     14.17mA    8.428mA    23.27mA
455mV     23.55mA    13.92mA    38.6mA
620mV     28.2mA     16.61mA    45.89mA
1.115V    33.56mA    19.78mA    53.54mA
2.38V     36.6mA     22.62mA    57.6mA
2.71V     41.55mA    27.09mA    59.61mA
3.15V     54.97mA    36.47mA    78.16mA
3.6V      72.84mA    47.64mA    107.4mA
[Pullup]
|Voltage   I(typ)   I(min)   I(max)
-1.8V     148.2mA    107.6mA    237.1mA
-1.46V    117.6mA    85.6mA     186.1mA
-1.13V    89.36mA    64.74mA    140.5mA
-800mV    62.24mA    44.62mA    97.43mA
-195mV    13.45mA    9.406mA    22.28mA
25mV      -1.58mA    -1.08mA    -2.674mA
190mV     -10.93mA   -7.424mA   -18.66mA
355mV     -18.44mA   -12.42mA   -31.8mA
520mV     -24.17mA   -16.11mA   -42.18mA
795mV     -29.88mA   -19.49mA   -53.5mA
1.07V     -31.75mA   -20.4mA    -58.22mA
3.6V      -37.02mA   -23.41mA   -69.25mA
[GND_clamp]
|Voltage   I(typ)   I(min)   I(max)
-1.8V     -1.831A    -1.488A    -2.421A
-1.097V   -451mA     -469.7mA   -431.6mA
-1.06V    -384.8mA   -420mA     -340.3mA
-986mV    -258.9mA   -323.6mA   -180.7mA
-949mV    -200.9mA   -277.4mA   -123.7mA
-912mV    -148.2mA   -232.8mA   -90.76mA
-838mV    -69.05mA   -150.6mA   -67.91mA
-801mV    -47.74mA   -114.1mA   -60.88mA
-690mV    -23.16mA   -33.02mA   -37.51mA
-579mV    -9.79mA    -5.846mA   -16.62mA
-357mV    -148.7uA   -66.38uA   -242.3uA
1.8V      0A         0A         0A
[POWER_clamp]
|Voltage   I(typ)   I(min)   I(max)
-1.8V     29.51mA    20.63mA    51.76mA
-1.345V   18.87mA    12.41mA    36.66mA
-938mV    10.26mA    6.136mA    22.4mA
-864mV    8.689mA    5.106mA    19.43mA
-790mV    7.087mA    4.117mA    16.01mA
-679mV    4.54mA     2.724mA    9.207mA
-605mV    2.701mA    1.871mA    5.102mA
-531mV    1.131mA    1.1mA      2.169mA
-457mV    338.1uA    470.7uA    629.2uA
-383mV    89.2uA     117.2uA    163.1uA
-272mV    9.185uA    9.485uA    15.7uA
1.8V      0A         0A         4.279nA
[Ramp]
| variable   typ   min   max
dV/dt_r   0.750/0.293n   0.575/0.492n   0.928/0.139n
dV/dt_f   0.770/0.278n   0.550/0.451n   0.933/0.159n
R_load = 50.000
[Rising Waveform]
R_fixture= 50.000
V_fixture= 0.0
V_fixture_min= 0.0
V_fixture_max= 0.0
|time   V(typ)   V(min)   V(max)
0s        5.055nV    47.21nV    2.607nV
701ps     -401.1uV   9.994uV    -37.65mV
924ps     -998.2uV   -13.51uV   1.3V
1.296ns   -48.66mV   -224.4uV   1.5V
1.443ns   322.8mV    -16.54uV   1.514V
1.779ns   1.062V     -1.872mV   1.532V
2.317ns   1.199V     -30.68mV   1.542V
2.642ns   1.219V     464.6mV    1.545V
4.096ns   1.246V     922.5mV    1.547V
20ns      1.25V      958.6mV    1.547V
[Rising Waveform]
R_fixture= 50.000
V_fixture= 1.800
V_fixture_min= 1.710
V_fixture_max= 1.890
|time   V(typ)   V(min)   V(max)
0s        516.8mV    793.5mV    334.2mV
647ps     516.1mV    793.5mV    342.1mV
706ps     516mV      793.5mV    581.8mV
841ps     516.5mV    793.5mV    1.697V
1.186ns   571.9mV    792.6mV    1.862V
1.511ns   1.654V     794.2mV    1.877V
1.879ns   1.773V     764.9mV    1.884V
2.503ns   1.789V     1.574V     1.889V
2.871ns   1.794V     1.688V     1.889V
20ns      1.8V       1.71V      1.89V
[Falling Waveform]
R_fixture= 50.000
V_fixture= 1.800
V_fixture_min= 1.710
V_fixture_max= 1.890
|time   V(typ)   V(min)   V(max)
0s        1.8V       1.71V      1.89V
727ps     1.8V       1.71V      1.949V
975ps     1.8V       1.71V      580.4mV
1.409ns   1.799V     1.71V      363.6mV
1.775ns   759.2mV    1.711V     345.6mV
2.343ns   551.9mV    1.739V     337.5mV
2.511ns   543mV      1.75V      336.4mV
3.102ns   528.4mV    990.3mV    334.8mV
3.806ns   521mV      834.6mV    334.3mV
20ns      516.8mV    793.5mV    334.2mV
[Falling Waveform]
R_fixture= 50.000
V_fixture= 0.0
V_fixture_min= 0.0
V_fixture_max= 0.0
|time   V(typ)   V(min)   V(max)
0s        1.25V      958.6mV    1.547V
691ps     1.25V      958.6mV    1.543V
878ps     1.25V      958.4mV    184.6mV
1.229ns   1.252V     958.5mV    21.69mV
1.582ns   144.3mV    959mV      8.646mV
1.955ns   20.34mV    958.7mV    3.513mV
2.271ns   11.13mV    905.1mV    1.684mV
2.775ns   4.978mV    93.12mV    548.4uV
3.331ns   2.305mV    12.35mV    179.6uV
20ns      -197nV     26.69nV    -204.8nV
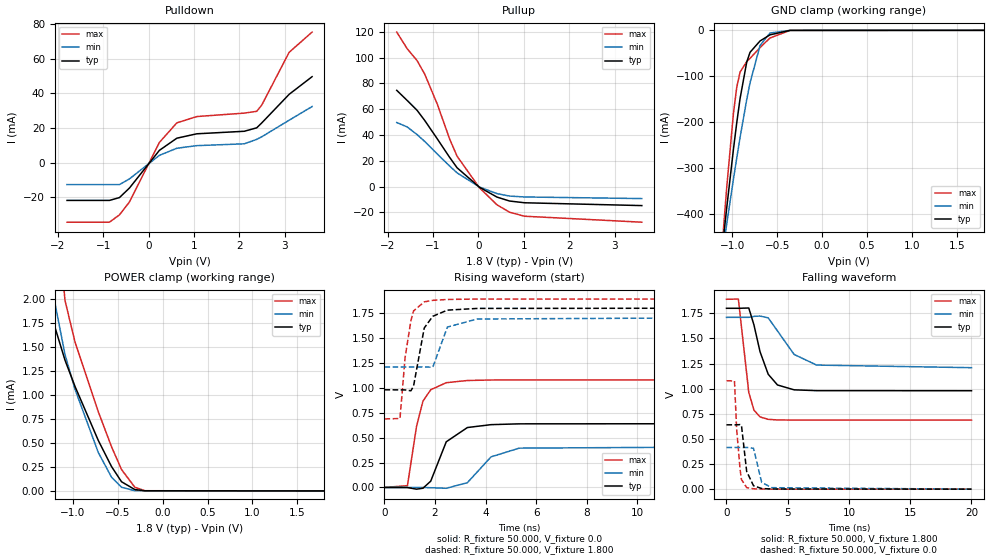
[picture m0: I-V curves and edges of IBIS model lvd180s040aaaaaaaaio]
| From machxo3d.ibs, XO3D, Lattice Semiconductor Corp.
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|   Model lvd180s040aaaaaaaaio
[Model] lvd180s040aaaaaaaaio
Model_type I/O
Polarity   Non-Inverting
Enable   Active-Low
Vinl =  0.630V
Vinh =  1.170V
Vmeas =  0.900V
Cref =  0.0F
Rref =  1.000M
Vref =  0.0V
C_comp   4.200pF   3.800pF   7.500pF
[Temperature Range]   25.000   0.105k   -40.000
[Voltage Range]   1.800V   1.710V   1.890V
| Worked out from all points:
|   slope of the pulldown table from 0 to 0.27 V, typ, clamps not added: 34 ohm
|   slope of the pullup table from 0 to 0.27 V, typ, clamps not added: 45.6 ohm
|   GND clamp passes 1 mA (typ) near -0.43 V on its own axis
|   POWER clamp passes 1 mA (typ) near -0.94 V on its own axis
|   rising waveform, R_fixture 50.000, V_fixture 0.0: 20-80 % time 694ps typ, 999ps min, 466ps max; typ from 0 V to 0.641 V
|   rising waveform, R_fixture 50.000, V_fixture 1.800: 20-80 % time 446ps typ, 441ps min, 339ps max; typ from 0.98 V to 1.8 V
|   falling waveform, R_fixture 50.000, V_fixture 1.800: 20-80 % time 1.16ns typ, 1.87ns min, 682ps max; typ from 1.8 V to 0.98 V
|   falling waveform, R_fixture 50.000, V_fixture 0.0: 20-80 % time 453ps typ, 477ps min, 363ps max; typ from 0.641 V to 0 V
[Pulldown]
|Voltage   I(typ)   I(min)   I(max)
-1.8V     -21.78mA   -12.65mA   -34.34mA
-865mV    -21.78mA   -12.65mA   -34.34mA
-645mV    -20.15mA   -12.65mA   -30.11mA
-425mV    -14.65mA   -9.378mA   -22.7mA
235mV     7.083mA    4.214mA    11.64mA
620mV     14.1mA     8.304mA    22.95mA
1.06V     16.64mA    9.805mA    26.58mA
2.105V    18.09mA    10.86mA    28.56mA
2.38V     20.08mA    13.42mA    29.6mA
2.49V     22.88mA    14.9mA     33.15mA
3.095V    39.41mA    24.47mA    63.64mA
3.6V      49.57mA    32.34mA    75.29mA
[Pullup]
|Voltage   I(typ)   I(min)   I(max)
-1.8V     74.68mA    49.68mA    119.9mA
-1.57V    66.83mA    46.26mA    107mA
-1.35V    59.09mA    40.26mA    97.67mA
-1.185V   51.36mA    35.04mA    87.37mA
-910mV    37.2mA     25.35mA    64.3mA
-635mV    22.67mA    15.91mA    36.96mA
-470mV    14.53mA    10.59mA    23.5mA
25mV      -631.9uA   -432.1uA   -1.07mA
410mV     -8.22mA    -5.519mA   -14.23mA
685mV     -11.26mA   -7.415mA   -19.94mA
1.015V    -12.62mA   -8.118mA   -23.07mA
3.6V      -14.81mA   -9.364mA   -27.7mA
[GND_clamp]
|Voltage   I(typ)   I(min)   I(max)
-1.8V     -1.831A    -1.488A    -2.421A
-1.097V   -451mA     -469.7mA   -431.6mA
-1.06V    -384.8mA   -420mA     -340.3mA
-986mV    -258.9mA   -323.6mA   -180.7mA
-949mV    -200.9mA   -277.4mA   -123.7mA
-912mV    -148.2mA   -232.8mA   -90.76mA
-838mV    -69.05mA   -150.6mA   -67.91mA
-801mV    -47.74mA   -114.1mA   -60.88mA
-690mV    -23.16mA   -33.02mA   -37.51mA
-579mV    -9.79mA    -5.846mA   -16.62mA
-357mV    -148.7uA   -66.38uA   -242.3uA
1.8V      0A         0A         0A
[POWER_clamp]
|Voltage   I(typ)   I(min)   I(max)
-1.8V     9.805mA    6.292mA    21.89mA
-1.271V   2.077mA    2.399mA    4.682mA
-1.234V   1.861mA    2.168mA    3.79mA
-1.197V   1.7mA      1.95mA     3.092mA
-1.086V   1.36mA     1.418mA    1.981mA
-975mV    1.088mA    1.058mA    1.55mA
-716mV    526uA      400.6uA    825.4uA
-568mV    252.9uA    142.1uA    458.4uA
-457mV    95.28uA    37.76uA    222.2uA
-309mV    14.3uA     2.005uA    38.47uA
-198mV    1.727uA    1.797uA    2.013uA
1.8V      0A         0A         4.279nA
[Ramp]
| variable   typ   min   max
dV/dt_r   0.384/0.691n   0.249/0.982n   0.647/0.467n
dV/dt_f   0.492/1.172n   0.301/1.846n   0.721/0.681n
R_load = 50.000
[Rising Waveform]
R_fixture= 50.000
V_fixture= 0.0
V_fixture_min= 0.0
V_fixture_max= 0.0
|time   V(typ)   V(min)   V(max)
0s        8.268nV    71.3nV     4.54nV
909ps     -915.7uV   -4.527uV   18.26mV
1.267ns   -17.07mV   -356.3uV   610.3mV
1.523ns   -7.788mV   -205.5uV   865.7mV
1.83ns    63.22mV    -2.669mV   980.4mV
2.445ns   458.3mV    -8.201mV   1.051V
3.281ns   601.2mV    47.97mV    1.073V
4.219ns   630.2mV    307.2mV    1.078V
5.335ns   638.2mV    394.6mV    1.079V
20ns      640.6mV    415.2mV    1.079V
[Rising Waveform]
R_fixture= 50.000
V_fixture= 1.800
V_fixture_min= 1.710
V_fixture_max= 1.890
|time   V(typ)   V(min)   V(max)
0s        979.8mV    1.209V     687.7mV
614ps     979mV      1.209V     691.7mV
815ps     978.7mV    1.209V     1.303V
1.045ns   969.9mV    1.209V     1.672V
1.15ns    1.016V     1.208V     1.771V
1.574ns   1.6V       1.209V     1.862V
1.911ns   1.717V     1.206V     1.877V
2.489ns   1.779V     1.609V     1.886V
3.667ns   1.796V     1.69V      1.89V
20ns      1.8V       1.71V      1.89V
[Falling Waveform]
R_fixture= 50.000
V_fixture= 1.800
V_fixture_min= 1.710
V_fixture_max= 1.890
|time   V(typ)   V(min)   V(max)
0s        1.8V       1.71V      1.89V
973ps     1.8V       1.71V      1.892V
1.822ns   1.803V     1.71V      963.7mV
2.244ns   1.635V     1.72V      786.8mV
2.742ns   1.368V     1.723V     718.9mV
3.407ns   1.144V     1.705V     694.9mV
4.164ns   1.037V     1.575V     689mV
5.522ns   988.7mV    1.341V     687.8mV
7.359ns   980.5mV    1.235V     687.7mV
20ns      979.7mV    1.209V     687.7mV
[Falling Waveform]
R_fixture= 50.000
V_fixture= 0.0
V_fixture_min= 0.0
V_fixture_max= 0.0
|time   V(typ)   V(min)   V(max)
0s        640.6mV    415.2mV    1.079V
656ps     640.1mV    415.2mV    1.077V
830ps     640.4mV    415.1mV    600.6mV
1.116ns   642.7mV    414.9mV    192.4mV
1.227ns   634mV      414.9mV    96.26mV
1.65ns    176.4mV    415.3mV    15.43mV
2.211ns   33.97mV    406.1mV    3.758mV
2.873ns   6.6mV      67.79mV    724.5uV
3.695ns   1.718mV    14.79mV    111.4uV
20ns      14.88nV    118nV      -13.4nV
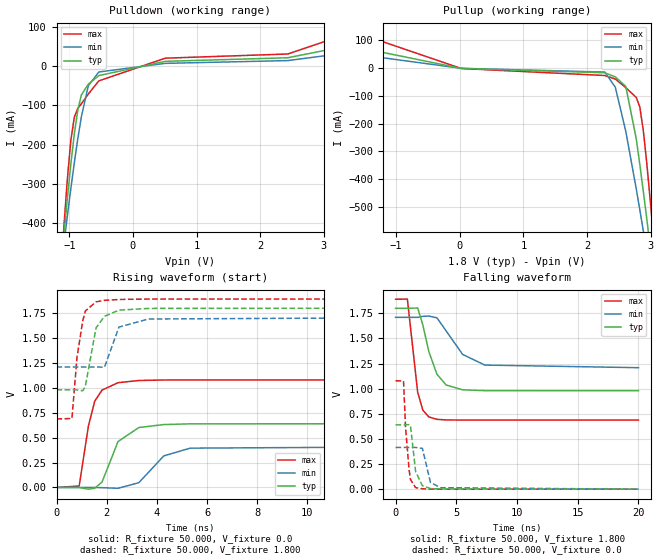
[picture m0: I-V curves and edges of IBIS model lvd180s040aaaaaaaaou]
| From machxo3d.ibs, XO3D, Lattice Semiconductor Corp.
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|   Model lvd180s040aaaaaaaaou
[Model] lvd180s040aaaaaaaaou
Model_type Output
Polarity   Non-Inverting
Enable   Active-High
Vmeas =  0.900V
Cref =  0.0F
Rref =  1.000M
Vref =  0.0V
C_comp   4.200pF   3.800pF   7.500pF
[Temperature Range]   25.000   0.105k   -40.000
[Voltage Range]   1.800V   1.710V   1.890V
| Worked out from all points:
|   slope of the pulldown table from 0 to 0.27 V, typ, clamps not added: 34 ohm
|   slope of the pullup table from 0 to 0.27 V, typ, clamps not added: 45.6 ohm
|   rising waveform, R_fixture 50.000, V_fixture 0.0: 20-80 % time 687ps typ, 991ps min, 466ps max; typ from 0 V to 0.641 V
|   rising waveform, R_fixture 50.000, V_fixture 1.800: 20-80 % time 446ps typ, 441ps min, 339ps max; typ from 0.98 V to 1.8 V
|   falling waveform, R_fixture 50.000, V_fixture 1.800: 20-80 % time 1.16ns typ, 1.87ns min, 682ps max; typ from 1.8 V to 0.98 V
|   falling waveform, R_fixture 50.000, V_fixture 0.0: 20-80 % time 453ps typ, 477ps min, 363ps max; typ from 0.641 V to 0 V
[Pulldown]
|Voltage   I(typ)   I(min)   I(max)
-1.8V     -1.832A    -1.488A    -2.422A
-1.085V   -433.5mA   -455.5mA   -411.7mA
-1.03V    -338.2mA   -382.8mA   -288.6mA
-975mV    -249.8mA   -312.6mA   -189.3mA
-920mV    -172.3mA   -246mA     -129.6mA
-865mV    -111.3mA   -184.3mA   -107.8mA
-810mV    -73.34mA   -129.4mA   -95.99mA
-700mV    -45.69mA   -49.6mA    -70.91mA
-535mV    -23.72mA   -14.54mA   -37.26mA
510mV     12.66mA    7.475mA    20.72mA
2.435V    21.8mA     14.56mA    31.41mA
3.6V      59.37mA    39.35mA    95.41mA
[Pullup]
|Voltage   I(typ)   I(min)   I(max)
-1.8V     84.49mA    55.97mA    141.8mA
25mV      -631.9uA   -432.1uA   -1.07mA
2.28V     -16.33mA   -13.87mA   -26.27mA
2.445V    -31.12mA   -68.47mA   -38.92mA
2.61V     -65.91mA   -227.8mA   -70.13mA
2.775V    -255.4mA   -435.7mA   -105.5mA
2.83V     -346.8mA   -510.1mA   -140mA
2.885V    -443.7mA   -586mA     -224.2mA
2.94V     -544.2mA   -663.1mA   -343.4mA
2.995V    -647.3mA   -741.1mA   -478.8mA
3.05V     -752.2mA   -819.9mA   -622.5mA
3.6V      -1.846A    -1.632A    -2.185A
[Ramp]
| variable   typ   min   max
dV/dt_r   0.384/0.691n   0.249/0.982n   0.647/0.467n
dV/dt_f   0.492/1.172n   0.301/1.846n   0.721/0.681n
R_load = 50.000
[Rising Waveform]
R_fixture= 50.000
V_fixture= 0.0
V_fixture_min= 0.0
V_fixture_max= 0.0
|time   V(typ)   V(min)   V(max)
0s        8.268nV    71.3nV     4.54nV
903ps     -862.2uV   -4.527uV   14.57mV
1.27ns    -17.07mV   -207.1uV   614.8mV
1.523ns   -7.788mV   -205.5uV   865.7mV
1.815ns   55mV       -2.381mV   977mV
2.453ns   461mV      -8.201mV   1.051V
3.281ns   601.2mV    47.97mV    1.073V
4.275ns   630.9mV    316.5mV    1.078V
5.326ns   638.2mV    394.4mV    1.079V
20ns      640.6mV    415.2mV    1.079V
[Rising Waveform]
R_fixture= 50.000
V_fixture= 1.800
V_fixture_min= 1.710
V_fixture_max= 1.890
|time   V(typ)   V(min)   V(max)
0s        979.8mV    1.209V     687.7mV
614ps     979mV      1.209V     691.7mV
815ps     978.7mV    1.209V     1.303V
1.045ns   969.9mV    1.209V     1.672V
1.15ns    1.016V     1.208V     1.771V
1.574ns   1.6V       1.209V     1.862V
1.911ns   1.717V     1.206V     1.877V
2.489ns   1.779V     1.609V     1.886V
3.667ns   1.796V     1.69V      1.89V
20ns      1.8V       1.71V      1.89V
[Falling Waveform]
R_fixture= 50.000
V_fixture= 1.800
V_fixture_min= 1.710
V_fixture_max= 1.890
|time   V(typ)   V(min)   V(max)
0s        1.8V       1.71V      1.89V
973ps     1.8V       1.71V      1.892V
1.822ns   1.803V     1.71V      963.7mV
2.244ns   1.635V     1.72V      786.8mV
2.741ns   1.369V     1.723V     718.9mV
3.407ns   1.144V     1.705V     694.9mV
4.164ns   1.037V     1.575V     689mV
5.522ns   988.7mV    1.341V     687.8mV
7.359ns   980.5mV    1.235V     687.7mV
20ns      979.7mV    1.209V     687.7mV
[Falling Waveform]
R_fixture= 50.000
V_fixture= 0.0
V_fixture_min= 0.0
V_fixture_max= 0.0
|time   V(typ)   V(min)   V(max)
0s        640.6mV    415.2mV    1.079V
656ps     640.1mV    415.2mV    1.077V
830ps     640.4mV    415.1mV    600.6mV
1.116ns   642.7mV    414.9mV    192.4mV
1.227ns   634mV      414.9mV    96.26mV
1.65ns    176.4mV    415.3mV    15.43mV
2.211ns   33.97mV    406.1mV    3.758mV
2.873ns   6.6mV      67.79mV    722.8uV
3.695ns   1.718mV    14.79mV    110.4uV
20ns      14.88nV    118nV      -13.4nV
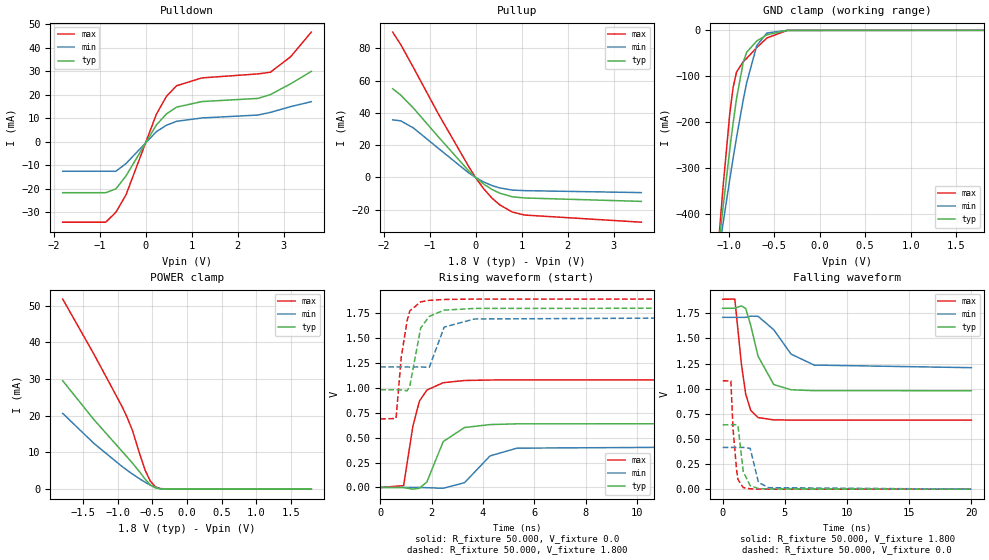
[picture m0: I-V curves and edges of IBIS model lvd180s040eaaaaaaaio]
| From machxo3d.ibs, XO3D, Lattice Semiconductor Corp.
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|   Model lvd180s040eaaaaaaaio
[Model] lvd180s040eaaaaaaaio
Model_type I/O
Polarity   Non-Inverting
Enable   Active-Low
Vinl =  0.630V
Vinh =  1.170V
Vmeas =  0.900V
Cref =  0.0F
Rref =  1.000M
Vref =  0.0V
C_comp   4.200pF   3.800pF   7.500pF
[Temperature Range]   25.000   0.105k   -40.000
[Voltage Range]   1.800V   1.710V   1.890V
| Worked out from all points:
|   slope of the pulldown table from 0 to 0.27 V, typ, clamps not added: 34 ohm
|   slope of the pullup table from 0 to 0.27 V, typ, clamps not added: 45.6 ohm
|   GND clamp passes 1 mA (typ) near -0.43 V on its own axis
|   POWER clamp passes 1 mA (typ) near -0.52 V on its own axis
|   rising waveform, R_fixture 50.000, V_fixture 0.0: 20-80 % time 687ps typ, 991ps min, 466ps max; typ from 0 V to 0.641 V
|   rising waveform, R_fixture 50.000, V_fixture 1.800: 20-80 % time 446ps typ, 441ps min, 339ps max; typ from 0.98 V to 1.8 V
|   falling waveform, R_fixture 50.000, V_fixture 1.800: 20-80 % time 1.16ns typ, 1.87ns min, 683ps max; typ from 1.8 V to 0.98 V
|   falling waveform, R_fixture 50.000, V_fixture 0.0: 20-80 % time 453ps typ, 477ps min, 363ps max; typ from 0.641 V to 0 V
[Pulldown]
|Voltage   I(typ)   I(min)   I(max)
-1.8V     -21.78mA   -12.65mA   -34.34mA
-865mV    -21.78mA   -12.65mA   -34.34mA
-645mV    -20.15mA   -12.65mA   -30.11mA
-425mV    -14.65mA   -9.378mA   -22.7mA
235mV     7.083mA    4.214mA    11.64mA
455mV     11.78mA    6.962mA    19.3mA
675mV     14.66mA    8.626mA    23.77mA
1.225V    17.02mA    10.04mA    27.1mA
2.435V    18.36mA    11.27mA    28.79mA
2.71V     19.97mA    12.4mA     29.5mA
3.15V     24.57mA    14.86mA    36.08mA
3.6V      29.87mA    16.97mA    46.6mA
[Pullup]
|Voltage   I(typ)   I(min)   I(max)
-1.8V     54.98mA    35.69mA    90.08mA
-1.625V   51.02mA    35.08mA    82.31mA
-1.35V    43mA       30.68mA    68.11mA
-800mV    24.9mA     17.85mA    38.97mA
-140mV    3.787mA    2.633mA    6.305mA
25mV      -631.9uA   -432.1uA   -1.07mA
190mV     -4.372mA   -2.969mA   -7.464mA
355mV     -7.378mA   -4.969mA   -12.72mA
520mV     -9.667mA   -6.446mA   -16.87mA
795mV     -11.95mA   -7.796mA   -21.4mA
1.07V     -12.7mA    -8.16mA    -23.29mA
3.6V      -14.81mA   -9.364mA   -27.7mA
[GND_clamp]
|Voltage   I(typ)   I(min)   I(max)
-1.8V     -1.831A    -1.488A    -2.421A
-1.097V   -451mA     -469.7mA   -431.6mA
-1.06V    -384.8mA   -420mA     -340.3mA
-986mV    -258.9mA   -323.6mA   -180.7mA
-949mV    -200.9mA   -277.4mA   -123.7mA
-912mV    -148.2mA   -232.8mA   -90.76mA
-838mV    -69.05mA   -150.6mA   -67.91mA
-801mV    -47.74mA   -114.1mA   -60.88mA
-690mV    -23.16mA   -33.02mA   -37.51mA
-579mV    -9.79mA    -5.846mA   -16.62mA
-357mV    -148.7uA   -66.38uA   -242.3uA
1.8V      0A         0A         0A
[POWER_clamp]
|Voltage   I(typ)   I(min)   I(max)
-1.8V     29.51mA    20.63mA    51.76mA
-1.345V   18.87mA    12.41mA    36.66mA
-938mV    10.26mA    6.136mA    22.4mA
-864mV    8.689mA    5.106mA    19.43mA
-790mV    7.087mA    4.117mA    16.01mA
-679mV    4.54mA     2.724mA    9.207mA
-605mV    2.701mA    1.871mA    5.102mA
-531mV    1.131mA    1.1mA      2.169mA
-457mV    338.1uA    470.7uA    629.2uA
-383mV    89.2uA     117.2uA    163.1uA
-272mV    9.185uA    9.485uA    15.71uA
1.8V      0A         0A         4.279nA
[Ramp]
| variable   typ   min   max
dV/dt_r   0.384/0.691n   0.249/0.982n   0.647/0.467n
dV/dt_f   0.492/1.172n   0.301/1.846n   0.721/0.681n
R_load = 50.000
[Rising Waveform]
R_fixture= 50.000
V_fixture= 0.0
V_fixture_min= 0.0
V_fixture_max= 0.0
|time   V(typ)   V(min)   V(max)
0s        8.268nV    71.3nV     4.54nV
909ps     -915.7uV   -4.527uV   18.26mV
1.267ns   -17.07mV   -356.3uV   610.3mV
1.523ns   -7.788mV   -205.5uV   865.7mV
1.815ns   55mV       -2.381mV   977mV
2.453ns   461mV      -8.201mV   1.051V
3.281ns   601.2mV    47.97mV    1.073V
4.275ns   630.9mV    316.5mV    1.078V
5.326ns   638.2mV    394.4mV    1.079V
20ns      640.6mV    415.2mV    1.079V
[Rising Waveform]
R_fixture= 50.000
V_fixture= 1.800
V_fixture_min= 1.710
V_fixture_max= 1.890
|time   V(typ)   V(min)   V(max)
0s        979.8mV    1.209V     687.7mV
614ps     979mV      1.209V     691.7mV
815ps     978.7mV    1.209V     1.303V
1.045ns   969.9mV    1.209V     1.672V
1.15ns    1.016V     1.208V     1.771V
1.574ns   1.6V       1.209V     1.862V
1.911ns   1.717V     1.206V     1.877V
2.489ns   1.779V     1.609V     1.886V
3.667ns   1.796V     1.69V      1.89V
20ns      1.8V       1.71V      1.89V
[Falling Waveform]
R_fixture= 50.000
V_fixture= 1.800
V_fixture_min= 1.710
V_fixture_max= 1.890
|time   V(typ)   V(min)   V(max)
0s        1.8V       1.71V      1.89V
973ps     1.8V       1.71V      1.892V
1.509ns   1.824V     1.71V      1.24V
1.852ns   1.798V     1.71V      944.5mV
2.253ns   1.63V      1.722V     784.6mV
2.845ns   1.323V     1.72V      712.5mV
4.111ns   1.041V     1.586V     689.4mV
5.501ns   989.2mV    1.344V     687.8mV
7.359ns   980.5mV    1.235V     687.7mV
20ns      979.7mV    1.209V     687.7mV
[Falling Waveform]
R_fixture= 50.000
V_fixture= 0.0
V_fixture_min= 0.0
V_fixture_max= 0.0
|time   V(typ)   V(min)   V(max)
0s        640.6mV    415.2mV    1.079V
656ps     640.1mV    415.2mV    1.077V
830ps     640.4mV    415.1mV    600.6mV
1.116ns   642.7mV    414.9mV    192.4mV
1.227ns   634mV      414.9mV    96.26mV
1.65ns    176.4mV    415.3mV    15.43mV
2.211ns   33.97mV    406.1mV    3.758mV
2.873ns   6.6mV      67.79mV    722.8uV
3.695ns   1.718mV    14.79mV    110.4uV
20ns      14.26nV    118nV      -13.4nV
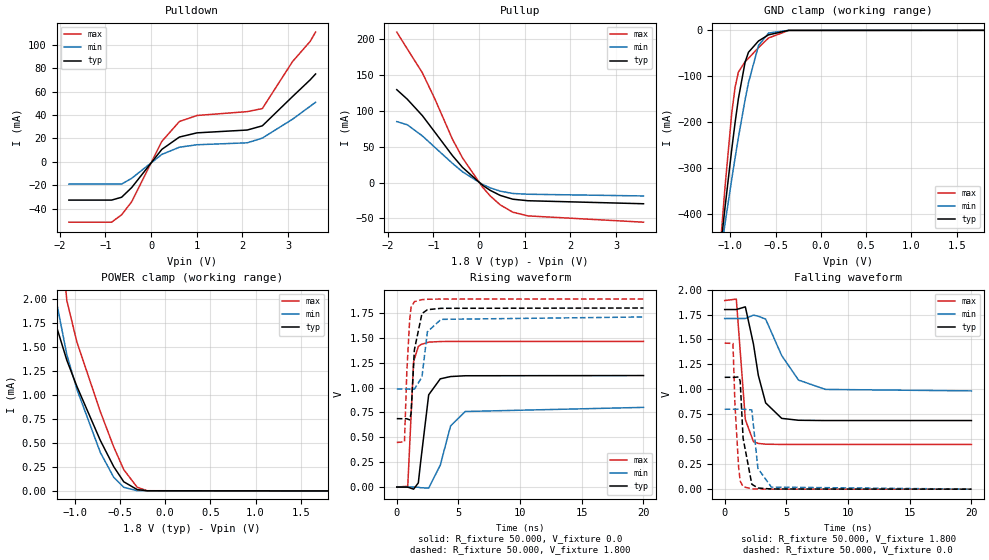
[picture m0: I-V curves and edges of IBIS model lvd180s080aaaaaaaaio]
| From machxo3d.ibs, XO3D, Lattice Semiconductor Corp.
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|   Model lvd180s080aaaaaaaaio
[Model] lvd180s080aaaaaaaaio
Model_type I/O
Polarity   Non-Inverting
Enable   Active-Low
Vinl =  0.630V
Vinh =  1.170V
Vmeas =  0.900V
Cref =  0.0F
Rref =  1.000M
Vref =  0.0V
C_comp   4.200pF   3.800pF   7.500pF
[Temperature Range]   25.000   0.105k   -40.000
[Voltage Range]   1.800V   1.710V   1.890V
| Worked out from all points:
|   slope of the pulldown table from 0 to 0.27 V, typ, clamps not added: 22.7 ohm
|   slope of the pullup table from 0 to 0.27 V, typ, clamps not added: 22.8 ohm
|   GND clamp passes 1 mA (typ) near -0.43 V on its own axis
|   POWER clamp passes 1 mA (typ) near -0.94 V on its own axis
|   rising waveform, R_fixture 50.000, V_fixture 0.0: 20-80 % time 616ps typ, 1.07ns min, 281ps max; typ from 0 V to 1.12 V
|   rising waveform, R_fixture 50.000, V_fixture 1.800: 20-80 % time 445ps typ, 439ps min, 312ps max; typ from 0.688 V to 1.8 V
|   falling waveform, R_fixture 50.000, V_fixture 1.800: 20-80 % time 1.01ns typ, 1.79ns min, 496ps max; typ from 1.8 V to 0.687 V
|   falling waveform, R_fixture 50.000, V_fixture 0.0: 20-80 % time 456ps typ, 467ps min, 344ps max; typ from 1.12 V to 0 V
[Pulldown]
|Voltage   I(typ)   I(min)   I(max)
-1.8V     -32.66mA   -18.98mA   -51.52mA
-865mV    -32.66mA   -18.98mA   -51.52mA
-645mV    -30.22mA   -18.98mA   -45.17mA
-425mV    -21.97mA   -14.07mA   -34.06mA
235mV     10.62mA    6.321mA    17.45mA
620mV     21.15mA    12.46mA    34.42mA
1.005V    24.72mA    14.56mA    39.54mA
2.105V    27.13mA    16.22mA    42.84mA
2.435V    30.72mA    20.25mA    45.46mA
3.095V    55.67mA    36.34mA    85.52mA
3.48V     69.89mA    47.35mA    102.7mA
3.6V      74.95mA    50.82mA    110.7mA
[Pullup]
|Voltage   I(typ)   I(min)   I(max)
-1.8V     129.8mA    85.23mA    210.3mA
-1.57V    116.5mA    80.76mA    186.8mA
-1.24V    93.53mA    65.21mA    153.4mA
-965mV    70.31mA    49.14mA    116.7mA
-580mV    37.52mA    26.75mA    60.33mA
-360mV    21.09mA    14.99mA    34.34mA
80mV      -3.923mA   -2.677mA   -6.658mA
245mV     -10.91mA   -7.39mA    -18.68mA
465mV     -17.97mA   -12.02mA   -31.22mA
740mV     -23.28mA   -15.26mA   -41.45mA
1.07V     -25.4mA    -16.32mA   -46.58mA
3.6V      -29.62mA   -18.73mA   -55.4mA
[GND_clamp]
|Voltage   I(typ)   I(min)   I(max)
-1.8V     -1.831A    -1.488A    -2.421A
-1.097V   -451mA     -469.7mA   -431.6mA
-1.06V    -384.8mA   -420mA     -340.3mA
-986mV    -258.9mA   -323.6mA   -180.7mA
-949mV    -200.9mA   -277.4mA   -123.7mA
-912mV    -148.2mA   -232.8mA   -90.76mA
-838mV    -69.05mA   -150.6mA   -67.91mA
-801mV    -47.74mA   -114.1mA   -60.88mA
-690mV    -23.16mA   -33.02mA   -37.51mA
-579mV    -9.79mA    -5.846mA   -16.62mA
-357mV    -148.7uA   -66.38uA   -242.3uA
1.8V      0A         0A         0A
[POWER_clamp]
|Voltage   I(typ)   I(min)   I(max)
-1.8V     9.805mA    6.292mA    21.89mA
-1.271V   2.077mA    2.399mA    4.682mA
-1.234V   1.861mA    2.168mA    3.79mA
-1.197V   1.7mA      1.95mA     3.092mA
-1.086V   1.36mA     1.418mA    1.981mA
-975mV    1.088mA    1.058mA    1.55mA
-716mV    526uA      400.6uA    825.4uA
-568mV    252.9uA    142.1uA    458.4uA
-457mV    95.28uA    37.76uA    222.2uA
-309mV    14.3uA     2.005uA    38.47uA
-198mV    1.727uA    1.797uA    2.013uA
1.8V      0A         0A         4.279nA
[Ramp]
| variable   typ   min   max
dV/dt_r   0.673/0.614n   0.481/1.061n   0.878/0.281n
dV/dt_f   0.668/1.013n   0.435/1.763n   0.865/0.496n
R_load = 50.000
[Rising Waveform]
R_fixture= 50.000
V_fixture= 0.0
V_fixture_min= 0.0
V_fixture_max= 0.0
|time   V(typ)   V(min)   V(max)
0s        6.274nV    56.81nV    3.312nV
890ps     -732.9uV   -8.981uV   7.667mV
1.365ns   -21.22mV   -281.2uV   1.262V
1.746ns   41.88mV    -1.689mV   1.413V
1.934ns   251.3mV    -6.882mV   1.432V
2.587ns   927.8mV    -10.18mV   1.457V
3.527ns   1.088V     220.2mV    1.463V
4.359ns   1.111V     614.2mV    1.464V
5.544ns   1.119V     759.7mV    1.464V
20ns      1.121V     801mV      1.464V
[Rising Waveform]
R_fixture= 50.000
V_fixture= 1.800
V_fixture_min= 1.710
V_fixture_max= 1.890
|time   V(typ)   V(min)   V(max)
0s        687.7mV    984.9mV    448.1mV
624ps     687mV      984.9mV    455.2mV
811ps     686.7mV    984.9mV    1.151V
1.049ns   675.9mV    984.2mV    1.689V
1.16ns    743.7mV    984mV      1.809V
1.426ns   1.379V     984.1mV    1.864V
2.04ns    1.744V     1.105V     1.884V
2.481ns   1.783V     1.561V     1.888V
3.586ns   1.797V     1.686V     1.89V
20ns      1.8V       1.71V      1.89V
[Falling Waveform]
R_fixture= 50.000
V_fixture= 1.800
V_fixture_min= 1.710
V_fixture_max= 1.890
|time   V(typ)   V(min)   V(max)
0s        1.8V       1.71V      1.89V
942ps     1.8V       1.71V      1.905V
1.673ns   1.827V     1.71V      697.5mV
2.331ns   1.454V     1.744V     476.3mV
2.725ns   1.141V     1.733V     458.2mV
3.32ns    864.5mV    1.704V     450.6mV
4.619ns   709.5mV    1.339V     448.2mV
5.988ns   690.5mV    1.093V     448.1mV
8.167ns   687.6mV    999.6mV    448mV
20ns      687.5mV    984.8mV    448mV
[Falling Waveform]
R_fixture= 50.000
V_fixture= 0.0
V_fixture_min= 0.0
V_fixture_max= 0.0
|time   V(typ)   V(min)   V(max)
0s        1.121V     801mV      1.464V
671ps     1.121V     801mV      1.46V
833ps     1.121V     800.9mV    841.9mV
1.13ns    1.125V     800.9mV    218.9mV
1.256ns   1.083V     801.2mV    81.33mV
1.491ns   510.6mV    801.4mV    23.93mV
2.199ns   49.46mV    793.6mV    3.623mV
2.693ns   11.51mV    207.5mV    1.044mV
3.784ns   1.932mV    20.65mV    84.94uV
20ns      16.57nV    122.7nV    -18.69nV
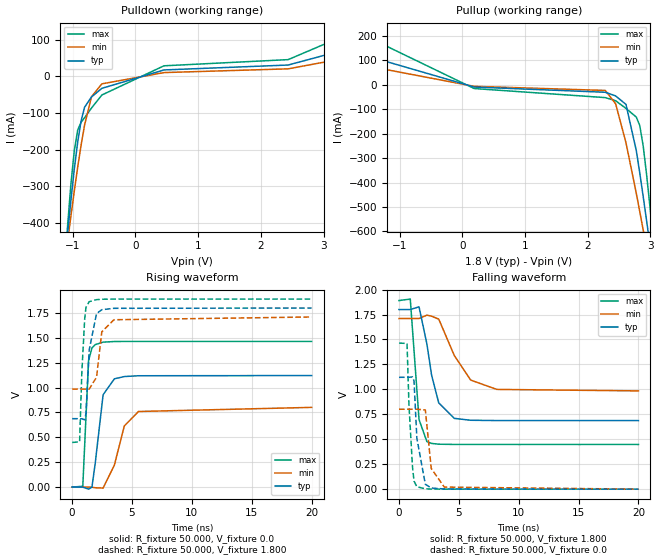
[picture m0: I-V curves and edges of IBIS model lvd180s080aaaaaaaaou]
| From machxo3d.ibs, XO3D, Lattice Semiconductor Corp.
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|   Model lvd180s080aaaaaaaaou
[Model] lvd180s080aaaaaaaaou
Model_type Output
Polarity   Non-Inverting
Enable   Active-High
Vmeas =  0.900V
Cref =  0.0F
Rref =  1.000M
Vref =  0.0V
C_comp   4.200pF   3.800pF   7.500pF
[Temperature Range]   25.000   0.105k   -40.000
[Voltage Range]   1.800V   1.710V   1.890V
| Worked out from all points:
|   slope of the pulldown table from 0 to 0.27 V, typ, clamps not added: 22.7 ohm
|   slope of the pullup table from 0 to 0.27 V, typ, clamps not added: 22.8 ohm
|   rising waveform, R_fixture 50.000, V_fixture 0.0: 20-80 % time 617ps typ, 1.07ns min, 281ps max; typ from 0 V to 1.12 V
|   rising waveform, R_fixture 50.000, V_fixture 1.800: 20-80 % time 445ps typ, 439ps min, 312ps max; typ from 0.688 V to 1.8 V
|   falling waveform, R_fixture 50.000, V_fixture 1.800: 20-80 % time 1.01ns typ, 1.79ns min, 497ps max; typ from 1.8 V to 0.687 V
|   falling waveform, R_fixture 50.000, V_fixture 0.0: 20-80 % time 456ps typ, 467ps min, 344ps max; typ from 1.12 V to 0 V
[Pulldown]
|Voltage   I(typ)   I(min)   I(max)
-1.8V     -1.832A    -1.489A    -2.422A
-1.085V   -435.6mA   -456.5mA   -416.8mA
-1.03V    -341.1mA   -383.9mA   -297.5mA
-975mV    -254mA     -314mA     -203.2mA
-920mV    -179mA     -247.8mA   -146.5mA
-865mV    -120.6mA   -186.7mA   -125mA
-810mV    -84.09mA   -132.7mA   -112.7mA
-700mV    -56.23mA   -55.37mA   -86.55mA
-535mV    -32.62mA   -20.37mA   -50.81mA
455mV     17.66mA    10.44mA    28.95mA
2.435V    31.09mA    20.67mA    45.87mA
3.6V      84.76mA    57.83mA    130.8mA
[Pullup]
|Voltage   I(typ)   I(min)   I(max)
-1.8V     139.6mA    91.52mA    232.2mA
190mV     -8.744mA   -5.939mA   -14.93mA
2.28V     -30.13mA   -22.66mA   -52mA
2.445V    -45.05mA   -77.36mA   -64.91mA
2.61V     -80mA      -236.8mA   -96.38mA
2.775V    -269.7mA   -444.8mA   -132mA
2.83V     -361mA     -519.2mA   -166.6mA
2.885V    -458mA     -595.1mA   -250.9mA
2.94V     -558.6mA   -672.2mA   -370.1mA
2.995V    -661.7mA   -750.3mA   -505.6mA
3.05V     -766.6mA   -829.1mA   -649.4mA
3.6V      -1.86A     -1.641A    -2.213A
[Ramp]
| variable   typ   min   max
dV/dt_r   0.673/0.614n   0.481/1.061n   0.878/0.281n
dV/dt_f   0.668/1.013n   0.435/1.763n   0.865/0.496n
R_load = 50.000
[Rising Waveform]
R_fixture= 50.000
V_fixture= 0.0
V_fixture_min= 0.0
V_fixture_max= 0.0
|time   V(typ)   V(min)   V(max)
0s        6.274nV    56.81nV    3.312nV
890ps     -732.9uV   -8.987uV   7.667mV
1.373ns   -21.22mV   24.02uV    1.271V
1.656ns   -994.3uV   -988.3uV   1.399V
1.933ns   243mV      -7.215mV   1.432V
2.587ns   927.8mV    -10.18mV   1.457V
3.527ns   1.088V     220.2mV    1.463V
4.359ns   1.111V     614.2mV    1.464V
5.544ns   1.119V     759.7mV    1.464V
20ns      1.121V     801mV      1.464V
[Rising Waveform]
R_fixture= 50.000
V_fixture= 1.800
V_fixture_min= 1.710
V_fixture_max= 1.890
|time   V(typ)   V(min)   V(max)
0s        687.7mV    984.9mV    448.1mV
624ps     687mV      984.9mV    455.2mV
811ps     686.7mV    984.9mV    1.151V
1.049ns   675.9mV    984.2mV    1.689V
1.16ns    743.7mV    984mV      1.809V
1.426ns   1.379V     984.1mV    1.864V
2.04ns    1.744V     1.105V     1.884V
2.481ns   1.783V     1.561V     1.888V
3.494ns   1.797V     1.682V     1.89V
20ns      1.8V       1.71V      1.89V
[Falling Waveform]
R_fixture= 50.000
V_fixture= 1.800
V_fixture_min= 1.710
V_fixture_max= 1.890
|time   V(typ)   V(min)   V(max)
0s        1.8V       1.71V      1.89V
942ps     1.8V       1.71V      1.905V
1.673ns   1.827V     1.71V      697.5mV
2.331ns   1.454V     1.744V     476.3mV
2.725ns   1.141V     1.733V     458.2mV
3.32ns    864.5mV    1.704V     450.6mV
4.619ns   709.5mV    1.339V     448.2mV
5.988ns   690.5mV    1.093V     448.1mV
8.167ns   687.6mV    999.6mV    448mV
20ns      687.5mV    984.8mV    448mV
[Falling Waveform]
R_fixture= 50.000
V_fixture= 0.0
V_fixture_min= 0.0
V_fixture_max= 0.0
|time   V(typ)   V(min)   V(max)
0s        1.121V     801mV      1.464V
671ps     1.121V     801mV      1.46V
833ps     1.121V     800.9mV    841.9mV
1.13ns    1.125V     800.9mV    218.9mV
1.256ns   1.083V     801.2mV    81.33mV
1.491ns   510.6mV    801.4mV    23.93mV
2.199ns   49.46mV    793.6mV    3.623mV
2.693ns   11.51mV    207.5mV    1.044mV
3.784ns   1.932mV    20.65mV    85.46uV
20ns      16.56nV    122.7nV    -18.69nV
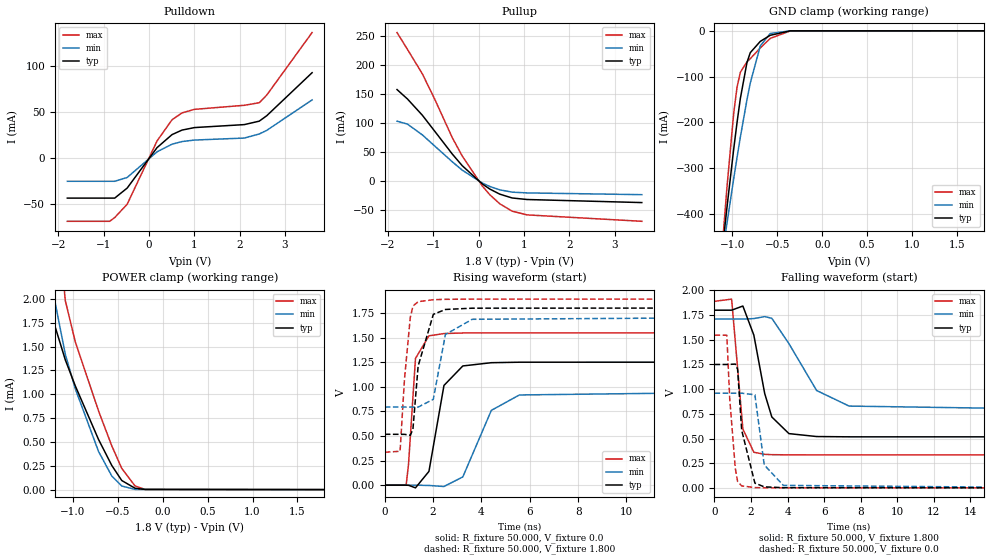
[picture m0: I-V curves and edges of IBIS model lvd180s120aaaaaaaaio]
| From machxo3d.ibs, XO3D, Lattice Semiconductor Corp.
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|   Model lvd180s120aaaaaaaaio
[Model] lvd180s120aaaaaaaaio
Model_type I/O
Polarity   Non-Inverting
Enable   Active-Low
Vinl =  0.630V
Vinh =  1.170V
Vmeas =  0.900V
Cref =  0.0F
Rref =  1.000M
Vref =  0.0V
C_comp   4.200pF   3.800pF   7.500pF
[Temperature Range]   25.000   0.105k   -40.000
[Voltage Range]   1.800V   1.710V   1.890V
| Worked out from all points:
|   slope of the pulldown table from 0 to 0.27 V, typ, clamps not added: 17 ohm
|   slope of the pullup table from 0 to 0.27 V, typ, clamps not added: 18.2 ohm
|   GND clamp passes 1 mA (typ) near -0.43 V on its own axis
|   POWER clamp passes 1 mA (typ) near -0.94 V on its own axis
|   rising waveform, R_fixture 50.000, V_fixture 0.0: 20-80 % time 534ps typ, 1.03ns min, 241ps max; typ from 0 V to 1.25 V
|   rising waveform, R_fixture 50.000, V_fixture 1.800: 20-80 % time 458ps typ, 434ps min, 300ps max; typ from 0.517 V to 1.8 V
|   falling waveform, R_fixture 50.000, V_fixture 1.800: 20-80 % time 875ps typ, 1.73ns min, 401ps max; typ from 1.8 V to 0.517 V
|   falling waveform, R_fixture 50.000, V_fixture 0.0: 20-80 % time 463ps typ, 474ps min, 336ps max; typ from 1.25 V to 0 V
[Pulldown]
|Voltage   I(typ)   I(min)   I(max)
-1.8V     -43.55mA   -25.31mA   -68.69mA
-865mV    -43.55mA   -25.31mA   -68.69mA
-755mV    -43.55mA   -25.31mA   -64.67mA
-480mV    -32.67mA   -21.16mA   -50.21mA
180mV     11.24mA    6.697mA    18.47mA
510mV     25.33mA    14.95mA    41.43mA
730mV     30.23mA    17.79mA    48.88mA
1.005V    32.96mA    19.42mA    52.72mA
2.105V    36.18mA    21.59mA    57.12mA
2.435V    39.95mA    26.03mA    59.92mA
2.6V      45.84mA    29.94mA    68.24mA
3.6V      92.46mA    62.94mA    136mA
[Pullup]
|Voltage   I(typ)   I(min)   I(max)
-1.8V     157.5mA    103.1mA    255.6mA
-1.57V    141.3mA    98.05mA    226.7mA
-1.24V    113.2mA    79.4mA     184.4mA
-965mV    85.45mA    60.06mA    140.4mA
-580mV    46.44mA    33.07mA    74.55mA
-360mV    26.36mA    18.72mA    42.93mA
80mV      -4.903mA   -3.346mA   -8.323mA
245mV     -13.64mA   -9.238mA   -23.35mA
465mV     -22.46mA   -15.03mA   -39.02mA
740mV     -29.1mA    -19.08mA   -51.81mA
1.07V     -31.75mA   -20.4mA    -58.22mA
3.6V      -37.02mA   -23.41mA   -69.25mA
[GND_clamp]
|Voltage   I(typ)   I(min)   I(max)
-1.8V     -1.831A    -1.488A    -2.421A
-1.097V   -451mA     -469.7mA   -431.6mA
-1.06V    -384.8mA   -420mA     -340.3mA
-986mV    -258.9mA   -323.6mA   -180.7mA
-949mV    -200.9mA   -277.4mA   -123.7mA
-912mV    -148.2mA   -232.8mA   -90.76mA
-838mV    -69.05mA   -150.6mA   -67.91mA
-801mV    -47.74mA   -114.1mA   -60.88mA
-690mV    -23.16mA   -33.02mA   -37.51mA
-579mV    -9.79mA    -5.846mA   -16.62mA
-357mV    -148.7uA   -66.38uA   -242.3uA
1.8V      0A         0A         0A
[POWER_clamp]
|Voltage   I(typ)   I(min)   I(max)
-1.8V     9.805mA    6.292mA    21.89mA
-1.271V   2.077mA    2.399mA    4.682mA
-1.234V   1.861mA    2.168mA    3.79mA
-1.197V   1.7mA      1.95mA     3.092mA
-1.086V   1.36mA     1.418mA    1.981mA
-975mV    1.088mA    1.058mA    1.55mA
-716mV    526uA      400.6uA    825.4uA
-568mV    252.9uA    142.1uA    458.4uA
-457mV    95.28uA    37.76uA    222.2uA
-309mV    14.3uA     2.005uA    38.47uA
-198mV    1.727uA    1.797uA    2.013uA
1.8V      0A         0A         4.279nA
[Ramp]
| variable   typ   min   max
dV/dt_r   0.750/0.533n   0.575/1.035n   0.928/0.239n
dV/dt_f   0.770/0.868n   0.550/1.738n   0.933/0.399n
R_load = 50.000
[Rising Waveform]
R_fixture= 50.000
V_fixture= 0.0
V_fixture_min= 0.0
V_fixture_max= 0.0
|time   V(typ)   V(min)   V(max)
0s        5.055nV    47.21nV    2.607nV
885ps     -658.2uV   -14.04uV   1.824mV
984ps     -1.816mV   -136.3uV   215.5mV
1.27ns    -27.83mV   -223.1uV   1.287V
1.828ns   139.9mV    -3.466mV   1.517V
2.449ns   1.013V     -14.09mV   1.54V
3.229ns   1.211V     83.34mV    1.546V
4.409ns   1.244V     759.7mV    1.547V
5.571ns   1.249V     916.2mV    1.547V
20ns      1.25V      958.6mV    1.547V
[Rising Waveform]
R_fixture= 50.000
V_fixture= 1.800
V_fixture_min= 1.710
V_fixture_max= 1.890
|time   V(typ)   V(min)   V(max)
0s        516.8mV    793.5mV    334.2mV
633ps     516.2mV    793.5mV    343.7mV
815ps     516.1mV    793.5mV    1.076V
1.054ns   506.5mV    792.9mV    1.701V
1.164ns   565.5mV    792.7mV    1.819V
1.38ns    1.21V      792.6mV    1.864V
2.008ns   1.735V     872.4mV    1.884V
2.509ns   1.785V     1.531V     1.888V
3.619ns   1.798V     1.685V     1.89V
20ns      1.8V       1.71V      1.89V
[Falling Waveform]
R_fixture= 50.000
V_fixture= 1.800
V_fixture_min= 1.710
V_fixture_max= 1.890
|time   V(typ)   V(min)   V(max)
0s        1.8V       1.71V      1.89V
937ps     1.8V       1.71V      1.912V
1.553ns   1.842V     1.71V      595.8mV
2.154ns   1.547V     1.715V     360.5mV
2.747ns   955.7mV    1.735V     339.7mV
3.136ns   718.3mV    1.718V     336.3mV
4.073ns   549.6mV    1.461V     334.4mV
5.587ns   519.9mV    986.3mV    334.2mV
7.366ns   517mV      828.5mV    334.2mV
20ns      516.8mV    793.4mV    334.2mV
[Falling Waveform]
R_fixture= 50.000
V_fixture= 0.0
V_fixture_min= 0.0
V_fixture_max= 0.0
|time   V(typ)   V(min)   V(max)
0s        1.25V      958.6mV    1.547V
675ps     1.25V      958.6mV    1.546V
834ps     1.251V     958.5mV    900.1mV
1.138ns   1.254V     958.6mV    198.3mV
1.264ns   1.202V     958.6mV    64.27mV
1.488ns   583.3mV    959mV      19.8mV
2.21ns    48.34mV    942.7mV    3.061mV
2.722ns   10.18mV    232.2mV    753.3uV
3.768ns   1.969mV    25.1mV     117uV
20ns      10.61nV    109.6nV    -15.16nV
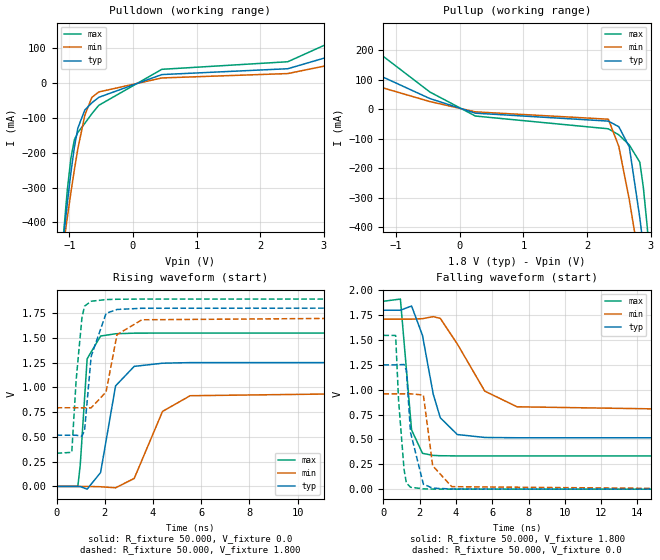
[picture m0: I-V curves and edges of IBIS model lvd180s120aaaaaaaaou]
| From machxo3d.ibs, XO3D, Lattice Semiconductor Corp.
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|   Model lvd180s120aaaaaaaaou
[Model] lvd180s120aaaaaaaaou
Model_type Output
Polarity   Non-Inverting
Enable   Active-High
Vmeas =  0.900V
Cref =  0.0F
Rref =  1.000M
Vref =  0.0V
C_comp   4.200pF   3.800pF   7.500pF
[Temperature Range]   25.000   0.105k   -40.000
[Voltage Range]   1.800V   1.710V   1.890V
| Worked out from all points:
|   slope of the pulldown table from 0 to 0.27 V, typ, clamps not added: 17 ohm
|   slope of the pullup table from 0 to 0.27 V, typ, clamps not added: 18.2 ohm
|   rising waveform, R_fixture 50.000, V_fixture 0.0: 20-80 % time 534ps typ, 1.04ns min, 241ps max; typ from 0 V to 1.25 V
|   rising waveform, R_fixture 50.000, V_fixture 1.800: 20-80 % time 458ps typ, 434ps min, 300ps max; typ from 0.517 V to 1.8 V
|   falling waveform, R_fixture 50.000, V_fixture 1.800: 20-80 % time 875ps typ, 1.73ns min, 401ps max; typ from 1.8 V to 0.517 V
|   falling waveform, R_fixture 50.000, V_fixture 0.0: 20-80 % time 463ps typ, 475ps min, 336ps max; typ from 1.25 V to 0 V
[Pulldown]
|Voltage   I(typ)   I(min)   I(max)
-1.8V     -1.833A    -1.489A    -2.423A
-1.085V   -437.7mA   -457.5mA   -421.9mA
-1.03V    -344mA     -385.1mA   -306.4mA
-975mV    -258.3mA   -315.5mA   -217.1mA
-920mV    -185.6mA   -249.6mA   -163.3mA
-865mV    -129.9mA   -189.1mA   -142.2mA
-755mV    -77.61mA   -92.79mA   -116.1mA
-645mV    -57.48mA   -41.86mA   -88.65mA
-535mV    -41.53mA   -26.19mA   -64.36mA
455mV     23.55mA    13.92mA    38.6mA
2.435V    40.32mA    26.45mA    60.32mA
3.6V      102.3mA    69.96mA    156.1mA
[Pullup]
|Voltage   I(typ)   I(min)   I(max)
-1.8V     167.3mA    109.4mA    277.5mA
-470mV    35.97mA    25.75mA    58.17mA
245mV     -13.64mA   -9.238mA   -23.35mA
2.335V    -40.52mA   -34.1mA    -66.62mA
2.5V      -59.56mA   -126.3mA   -87.07mA
2.665V    -128.1mA   -307.3mA   -121.5mA
2.83V     -368.2mA   -523.7mA   -179.9mA
2.885V    -465.2mA   -599.6mA   -264.3mA
2.94V     -565.8mA   -676.7mA   -383.5mA
2.995V    -668.9mA   -754.8mA   -519mA
3.05V     -773.9mA   -833.7mA   -662.9mA
3.6V      -1.868A    -1.646A    -2.227A
[Ramp]
| variable   typ   min   max
dV/dt_r   0.750/0.533n   0.575/1.035n   0.928/0.239n
dV/dt_f   0.770/0.868n   0.550/1.738n   0.933/0.399n
R_load = 50.000
[Rising Waveform]
R_fixture= 50.000
V_fixture= 0.0
V_fixture_min= 0.0
V_fixture_max= 0.0
|time   V(typ)   V(min)   V(max)
0s        5.055nV    47.21nV    2.607nV
885ps     -658.1uV   -14.04uV   1.824mV
984ps     -1.816mV   -136.3uV   215.5mV
1.27ns    -27.83mV   -223.1uV   1.287V
1.828ns   139.9mV    -3.466mV   1.517V
2.45ns    1.014V     -14.09mV   1.54V
3.223ns   1.211V     80.22mV    1.546V
4.398ns   1.243V     756.4mV    1.547V
5.544ns   1.249V     914.9mV    1.547V
20ns      1.25V      958.6mV    1.547V
[Rising Waveform]
R_fixture= 50.000
V_fixture= 1.800
V_fixture_min= 1.710
V_fixture_max= 1.890
|time   V(typ)   V(min)   V(max)
0s        516.8mV    793.5mV    334.2mV
633ps     516.2mV    793.5mV    343.7mV
815ps     516.1mV    793.5mV    1.076V
1.054ns   506.5mV    792.9mV    1.701V
1.164ns   565.5mV    792.7mV    1.819V
1.437ns   1.312V     792.7mV    1.868V
2.056ns   1.746V     952.8mV    1.885V
2.509ns   1.785V     1.531V     1.888V
3.539ns   1.797V     1.681V     1.89V
20ns      1.8V       1.71V      1.89V
[Falling Waveform]
R_fixture= 50.000
V_fixture= 1.800
V_fixture_min= 1.710
V_fixture_max= 1.890
|time   V(typ)   V(min)   V(max)
0s        1.8V       1.71V      1.89V
937ps     1.8V       1.71V      1.912V
1.553ns   1.842V     1.71V      595.8mV
2.154ns   1.547V     1.715V     360.5mV
2.747ns   955.7mV    1.735V     339.7mV
3.136ns   718.3mV    1.718V     336.3mV
4.073ns   549.6mV    1.461V     334.4mV
5.587ns   519.9mV    986.3mV    334.2mV
7.366ns   517mV      828.5mV    334.2mV
20ns      516.8mV    793.4mV    334.2mV
[Falling Waveform]
R_fixture= 50.000
V_fixture= 0.0
V_fixture_min= 0.0
V_fixture_max= 0.0
|time   V(typ)   V(min)   V(max)
0s        1.25V      958.6mV    1.547V
675ps     1.25V      958.6mV    1.546V
834ps     1.251V     958.5mV    900.1mV
1.138ns   1.254V     958.6mV    198.3mV
1.266ns   1.198V     958.6mV    63.28mV
1.494ns   572.2mV    959mV      19.31mV
2.204ns   49.68mV    946.8mV    3.132mV
2.717ns   10.18mV    235.4mV    774.7uV
3.768ns   1.969mV    25.1mV     66.89uV
20ns      10.61nV    109.6nV    -15.16nV
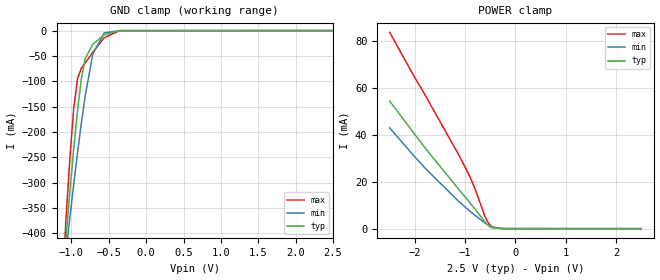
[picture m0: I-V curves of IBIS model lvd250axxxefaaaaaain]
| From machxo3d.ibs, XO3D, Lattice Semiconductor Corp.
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|   Model lvd250axxxefaaaaaain
[Model] lvd250axxxefaaaaaain
Model_type Input
Polarity   Non-Inverting
Enable   Active-High
Vinl =  0.700V
Vinh =  1.700V
C_comp   4.200pF   3.800pF   7.500pF
[Temperature Range]   25.000   0.105k   -40.000
[Voltage Range]   2.500V   2.380V   2.630V
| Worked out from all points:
|   GND clamp passes 1 mA (typ) near -0.43 V on its own axis
|   POWER clamp passes 1 mA (typ) near -0.52 V on its own axis
[GND_clamp]
|Voltage   I(typ)   I(min)   I(max)
-2.5V     -3.262A    -2.545A    -4.485A
-1.123V   -498.5mA   -505.1mA   -498.3mA
-1.072V   -406.1mA   -436mA     -369.4mA
-1.021V   -317.1mA   -368.7mA   -251mA
-970mV    -233.3mA   -303.5mA   -153.4mA
-919mV    -157.7mA   -241.1mA   -95.21mA
-868mV    -95.78mA   -182.7mA   -74.26mA
-817mV    -55.48mA   -129.4mA   -63.96mA
-715mV    -26.89mA   -46.57mA   -42.82mA
-562mV    -8.195mA   -4.484mA   -13.98mA
-358mV    -153.4uA   -68.26uA   -250.2uA
2.5V      0A         0A         0A
[POWER_clamp]
|Voltage   I(typ)   I(min)   I(max)
-2.5V     54.23mA    42.85mA    83.47mA
-2.039V   41.12mA    31.42mA    65.66mA
-1.784V   33.99mA    25.46mA    56.34mA
-1.121V   16.56mA    11.45mA    31.14mA
-917mV    11.31mA    7.645mA    22.57mA
-815mV    8.625mA    5.831mA    17.67mA
-611mV    2.953mA    2.495mA    5.465mA
-560mV    1.702mA    1.758mA    3.215mA
-509mV    833.1uA    1.093mA    1.608mA
-458mV    359uA      552.7uA    679.3uA
-254mV    7.444uA    6.927uA    15.57uA
2.5V      0A         0A         3.059nA
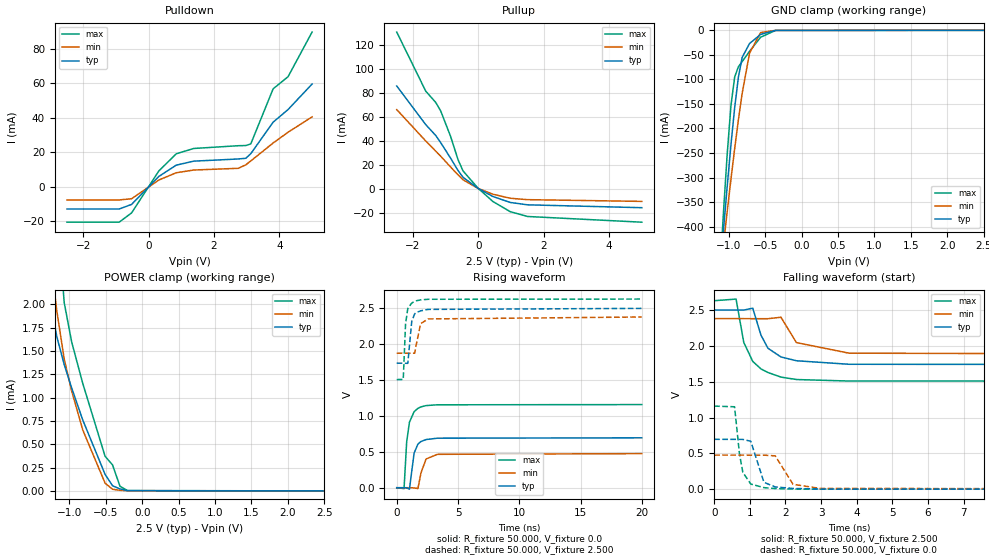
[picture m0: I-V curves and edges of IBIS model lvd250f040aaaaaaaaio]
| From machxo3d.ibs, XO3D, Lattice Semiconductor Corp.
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|   Model lvd250f040aaaaaaaaio
[Model] lvd250f040aaaaaaaaio
Model_type I/O
Polarity   Non-Inverting
Enable   Active-Low
Vinl =  0.700V
Vinh =  1.700V
Vmeas =  1.250V
Cref =  0.0F
Rref =  1.000M
Vref =  0.0V
C_comp   4.200pF   3.800pF   7.500pF
[Temperature Range]   25.000   0.105k   -40.000
[Voltage Range]   2.500V   2.380V   2.630V
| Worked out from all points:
|   slope of the pulldown table from 0 to 0.375 V, typ, clamps not added: 54.4 ohm
|   slope of the pullup table from 0 to 0.375 V, typ, clamps not added: 65.1 ohm
|   GND clamp passes 1 mA (typ) near -0.43 V on its own axis
|   POWER clamp passes 1 mA (typ) near -0.92 V on its own axis
|   rising waveform, R_fixture 50.000, V_fixture 0.0: 20-80 % time 400ps typ, 451ps min, 379ps max; typ from 0 V to 0.696 V
|   rising waveform, R_fixture 50.000, V_fixture 2.500: 20-80 % time 264ps typ, 359ps min, 187ps max; typ from 1.74 V to 2.5 V
|   falling waveform, R_fixture 50.000, V_fixture 2.500: 20-80 % time 491ps typ, 507ps min, 480ps max; typ from 2.5 V to 1.74 V
|   falling waveform, R_fixture 50.000, V_fixture 0.0: 20-80 % time 236ps typ, 319ps min, 175ps max; typ from 0.696 V to 0 V
[Pulldown]
|Voltage   I(typ)   I(min)   I(max)
-2.5V     -13.08mA   -7.815mA   -20.75mA
-904mV    -13.08mA   -7.815mA   -20.75mA
-524mV    -10.41mA   -7.109mA   -15.34mA
312mV     5.902mA    3.803mA    9.102mA
844mV     12.43mA    8.006mA    19.04mA
1.376V    14.75mA    9.586mA    22.12mA
2.744V    16.02mA    10.59mA    23.73mA
2.972V    16.42mA    12.63mA    23.83mA
3.124V    19.09mA    14.86mA    24.78mA
3.808V    37.42mA    25.31mA    56.82mA
4.264V    44.75mA    31.56mA    63.84mA
5V        59.6mA     40.51mA    89.81mA
[Pullup]
|Voltage   I(typ)   I(min)   I(max)
-2.5V     85.63mA    65.9mA     130.6mA
-1.612V   53.35mA    39.7mA     81.3mA
-1.308V   44.35mA    31.25mA    71.95mA
-1.156V   38.4mA     27.04mA    64.86mA
-852mV    25.37mA    18.02mA    43.55mA
-624mV    15.09mA    11.42mA    24.13mA
-472mV    9.428mA    7.348mA    14.75mA
-16mV     282.9uA    204.1uA    454.4uA
440mV     -6.588mA   -4.693mA   -10.74mA
972mV     -11.57mA   -8.084mA   -19.27mA
1.504V    -13.57mA   -9.251mA   -23.3mA
5V        -15.96mA   -10.7mA    -28.06mA
[GND_clamp]
|Voltage   I(typ)   I(min)   I(max)
-2.5V     -3.262A    -2.545A    -4.485A
-1.123V   -498.5mA   -505.1mA   -498.3mA
-1.072V   -406.1mA   -436mA     -369.4mA
-1.021V   -317.1mA   -368.7mA   -251mA
-970mV    -233.3mA   -303.5mA   -153.4mA
-919mV    -157.7mA   -241.1mA   -95.21mA
-868mV    -95.78mA   -182.7mA   -74.26mA
-817mV    -55.48mA   -129.4mA   -63.96mA
-715mV    -26.89mA   -46.57mA   -42.82mA
-562mV    -8.195mA   -4.484mA   -13.98mA
-358mV    -153.4uA   -68.26uA   -250.2uA
2.5V      0A         0A         0A
[POWER_clamp]
|Voltage   I(typ)   I(min)   I(max)
-2.5V     19.37mA    14.08mA    35.47mA
-1.274V   2.185mA    2.634mA    5.424mA
-1.223V   1.865mA    2.265mA    4.051mA
-1.172V   1.654mA    1.93mA     3.052mA
-1.07V    1.353mA    1.412mA    2.016mA
-968mV    1.104mA    1.071mA    1.597mA
-815mV    758.5uA    651.8uA    1.15mA
-509mV    176.7uA    82.75uA    370.5uA
-407mV    55.24uA    18.01uA    278.8uA
-305mV    21.57uA    6.5uA      49.89uA
-203mV    2.401uA    2.25uA     4.21uA
2.5V      0A         0A         3.059nA
[Ramp]
| variable   typ   min   max
dV/dt_r   0.417/0.398n   0.285/0.445n   0.695/0.379n
dV/dt_f   0.459/0.490n   0.303/0.514n   0.673/0.475n
R_load = 50.000
[Rising Waveform]
R_fixture= 50.000
V_fixture= 0.0
V_fixture_min= 0.0
V_fixture_max= 0.0
|time   V(typ)   V(min)   V(max)
0s        15.97nV    94.97nV    53.01nV
597ps     -211.5uV   12.23uV    -12.27mV
811ps     -1.403mV   12.23uV    640.6mV
1.036ns   -20.2mV    -63.78uV   912.8mV
1.418ns   482.7mV    -3.106mV   1.06V
1.73ns    608.7mV    -11.26mV   1.106V
1.977ns   644.1mV    205.7mV    1.127V
2.393ns   671.3mV    400.4mV    1.145V
3.315ns   690.5mV    465.5mV    1.156V
20ns      695.7mV    475.2mV    1.159V
[Rising Waveform]
R_fixture= 50.000
V_fixture= 2.500
V_fixture_min= 2.380
V_fixture_max= 2.630
|time   V(typ)   V(min)   V(max)
0s        1.736V     1.876V     1.508V
531ps     1.736V     1.876V     1.509V
720ps     1.735V     1.876V     2.283V
904ps     1.734V     1.876V     2.499V
1.223ns   2.317V     1.876V     2.574V
1.463ns   2.424V     1.875V     2.598V
1.598ns   2.442V     2V         2.606V
1.953ns   2.466V     2.288V     2.619V
2.566ns   2.486V     2.353V     2.627V
20ns      2.5V       2.38V      2.63V
[Falling Waveform]
R_fixture= 50.000
V_fixture= 2.500
V_fixture_min= 2.380
V_fixture_max= 2.630
|time   V(typ)   V(min)   V(max)
0s        2.5V       2.38V      2.63V
614ps     2.499V     2.38V      2.653V
830ps     2.499V     2.38V      2.049V
1.082ns   2.526V     2.379V     1.783V
1.313ns   2.149V     2.379V     1.678V
1.51ns    1.966V     2.379V     1.628V
1.874ns   1.845V     2.399V     1.564V
2.309ns   1.792V     2.045V     1.53V
3.783ns   1.743V     1.898V     1.509V
20ns      1.736V     1.876V     1.508V
[Falling Waveform]
R_fixture= 50.000
V_fixture= 0.0
V_fixture_min= 0.0
V_fixture_max= 0.0
|time   V(typ)   V(min)   V(max)
0s        695.7mV    475.1mV    1.159V
572ps     694.9mV    475mV      1.15V
710ps     694.6mV    475.1mV    489.9mV
804ps     694.6mV    475mV      235.1mV
1.027ns   668.3mV    474.5mV    71.24mV
1.397ns   95.38mV    474.7mV    21.32mV
1.714ns   30.99mV    464.5mV    8.749mV
2.214ns   10.02mV    67.49mV    2.31mV
2.976ns   2.339mV    10.42mV    318.9uV
20ns      -32.02nV   -55.69nV   -36.95nV
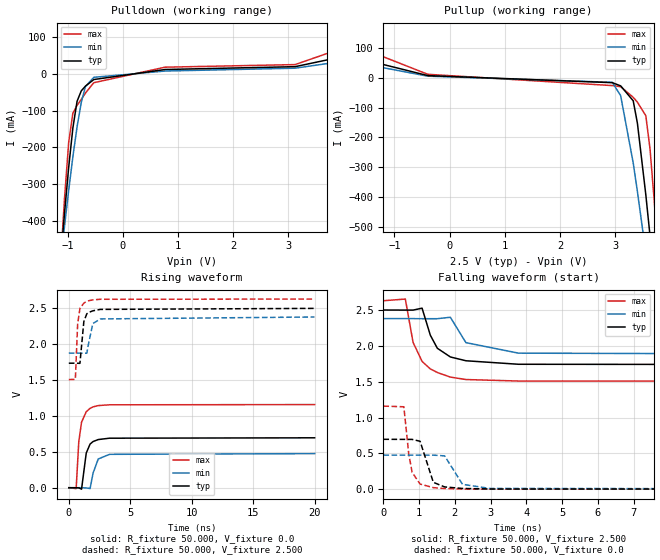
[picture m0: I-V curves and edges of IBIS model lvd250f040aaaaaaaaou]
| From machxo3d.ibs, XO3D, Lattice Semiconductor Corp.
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|   Model lvd250f040aaaaaaaaou
[Model] lvd250f040aaaaaaaaou
Model_type Output
Polarity   Non-Inverting
Enable   Active-High
Vmeas =  1.250V
Cref =  0.0F
Rref =  1.000M
Vref =  0.0V
C_comp   4.200pF   3.800pF   7.500pF
[Temperature Range]   25.000   0.105k   -40.000
[Voltage Range]   2.500V   2.380V   2.630V
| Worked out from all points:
|   slope of the pulldown table from 0 to 0.375 V, typ, clamps not added: 54.4 ohm
|   slope of the pullup table from 0 to 0.375 V, typ, clamps not added: 65.1 ohm
|   rising waveform, R_fixture 50.000, V_fixture 0.0: 20-80 % time 399ps typ, 451ps min, 379ps max; typ from 0 V to 0.696 V
|   rising waveform, R_fixture 50.000, V_fixture 2.500: 20-80 % time 264ps typ, 359ps min, 187ps max; typ from 1.74 V to 2.5 V
|   falling waveform, R_fixture 50.000, V_fixture 2.500: 20-80 % time 491ps typ, 507ps min, 480ps max; typ from 2.5 V to 1.74 V
|   falling waveform, R_fixture 50.000, V_fixture 0.0: 20-80 % time 236ps typ, 319ps min, 175ps max; typ from 0.696 V to 0 V
[Pulldown]
|Voltage   I(typ)   I(min)   I(max)
-2.5V     -3.262A    -2.545A    -4.486A
-1.132V   -517.4mA   -518.6mA   -526.7mA
-1.056V   -381.2mA   -416.2mA   -341mA
-980mV    -255.2mA   -318mA     -187.6mA
-904mV    -147.7mA   -226.3mA   -107.2mA
-828mV    -74.92mA   -144.7mA   -86.02mA
-752mV    -46.52mA   -78.35mA   -69.69mA
-676mV    -33.59mA   -34.6mA    -52.52mA
-524mV    -15.53mA   -9.507mA   -24.14mA
768mV     11.78mA    7.58mA     18.08mA
3.124V    19.46mA    15.34mA    25.12mA
5V        78.96mA    55.94mA    123mA
[Pullup]
|Voltage   I(typ)   I(min)   I(max)
-2.5V     105mA      79.97mA    166.1mA
-396mV    7.655mA    5.733mA    12.04mA
2.948V    -16.13mA   -14.92mA   -25.93mA
3.1V      -26.84mA   -59.7mA    -29.58mA
3.328V    -77.1mA    -286.3mA   -65.5mA
3.404V    -152.8mA   -382.7mA   -81.82mA
3.556V    -392.9mA   -588.5mA   -127mA
3.632V    -530.3mA   -695.3mA   -238mA
3.708V    -672.8mA   -803.8mA   -410.9mA
3.784V    -818.6mA   -913.6mA   -606.5mA
3.86V     -966.6mA   -1.024A    -812.2mA
5V        -3.278A    -2.738A    -4.128A
[Ramp]
| variable   typ   min   max
dV/dt_r   0.417/0.398n   0.285/0.445n   0.695/0.379n
dV/dt_f   0.459/0.490n   0.303/0.514n   0.673/0.475n
R_load = 50.000
[Rising Waveform]
R_fixture= 50.000
V_fixture= 0.0
V_fixture_min= 0.0
V_fixture_max= 0.0
|time   V(typ)   V(min)   V(max)
0s        15.97nV    94.97nV    53.01nV
597ps     -211.4uV   12.22uV    -12.27mV
811ps     -1.403mV   12.22uV    640.6mV
1.036ns   -20.2mV    -63.78uV   912.8mV
1.418ns   482.7mV    -3.106mV   1.06V
1.73ns    608.7mV    -11.26mV   1.106V
1.977ns   644.1mV    205.7mV    1.127V
2.393ns   671.3mV    400.4mV    1.145V
3.315ns   690.5mV    465.5mV    1.156V
20ns      695.7mV    475.2mV    1.159V
[Rising Waveform]
R_fixture= 50.000
V_fixture= 2.500
V_fixture_min= 2.380
V_fixture_max= 2.630
|time   V(typ)   V(min)   V(max)
0s        1.736V     1.876V     1.508V
531ps     1.736V     1.876V     1.509V
720ps     1.735V     1.876V     2.283V
904ps     1.734V     1.876V     2.499V
1.223ns   2.317V     1.876V     2.574V
1.463ns   2.424V     1.875V     2.598V
1.598ns   2.442V     2V         2.606V
1.953ns   2.466V     2.288V     2.619V
2.566ns   2.486V     2.353V     2.627V
20ns      2.5V       2.38V      2.63V
[Falling Waveform]
R_fixture= 50.000
V_fixture= 2.500
V_fixture_min= 2.380
V_fixture_max= 2.630
|time   V(typ)   V(min)   V(max)
0s        2.5V       2.38V      2.63V
614ps     2.499V     2.38V      2.653V
830ps     2.499V     2.38V      2.049V
1.082ns   2.526V     2.379V     1.783V
1.313ns   2.149V     2.379V     1.678V
1.51ns    1.966V     2.379V     1.628V
1.874ns   1.845V     2.399V     1.564V
2.309ns   1.792V     2.045V     1.53V
3.783ns   1.743V     1.898V     1.509V
20ns      1.736V     1.876V     1.508V
[Falling Waveform]
R_fixture= 50.000
V_fixture= 0.0
V_fixture_min= 0.0
V_fixture_max= 0.0
|time   V(typ)   V(min)   V(max)
0s        695.7mV    475.1mV    1.159V
572ps     694.9mV    475mV      1.15V
710ps     694.6mV    475.1mV    489.9mV
804ps     694.6mV    475mV      235.1mV
1.027ns   668.3mV    474.5mV    71.24mV
1.397ns   95.38mV    474.7mV    21.32mV
1.714ns   30.99mV    464.5mV    8.749mV
2.214ns   10.02mV    67.49mV    2.31mV
2.976ns   2.339mV    10.42mV    318.9uV
20ns      -32.02nV   -55.69nV   -36.95nV
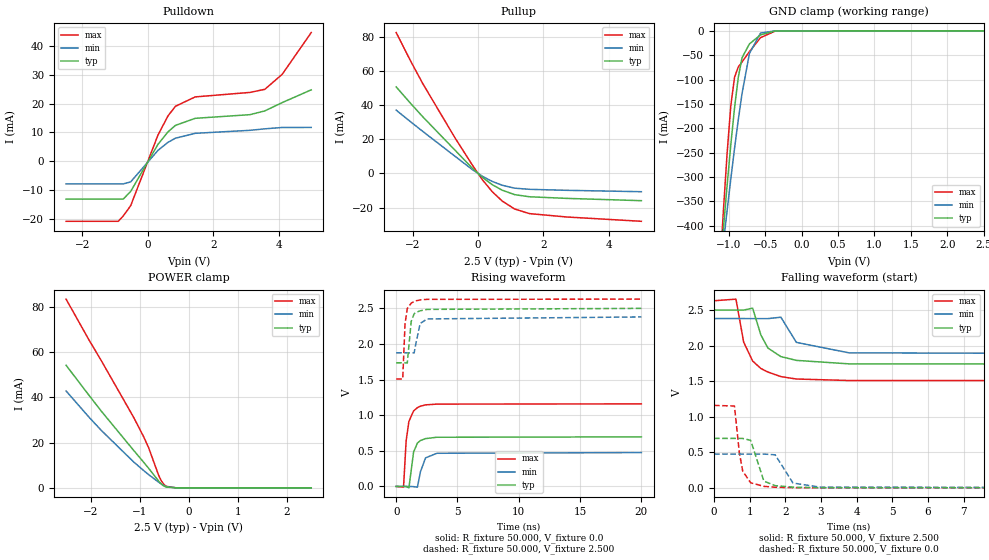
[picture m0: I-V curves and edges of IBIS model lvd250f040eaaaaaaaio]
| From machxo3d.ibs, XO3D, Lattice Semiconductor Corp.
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|   Model lvd250f040eaaaaaaaio
[Model] lvd250f040eaaaaaaaio
Model_type I/O
Polarity   Non-Inverting
Enable   Active-Low
Vinl =  0.700V
Vinh =  1.700V
Vmeas =  1.250V
Cref =  0.0F
Rref =  1.000M
Vref =  0.0V
C_comp   4.200pF   3.800pF   7.500pF
[Temperature Range]   25.000   0.105k   -40.000
[Voltage Range]   2.500V   2.380V   2.630V
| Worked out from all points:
|   slope of the pulldown table from 0 to 0.375 V, typ, clamps not added: 54.4 ohm
|   slope of the pullup table from 0 to 0.375 V, typ, clamps not added: 65.1 ohm
|   GND clamp passes 1 mA (typ) near -0.43 V on its own axis
|   POWER clamp passes 1 mA (typ) near -0.52 V on its own axis
|   rising waveform, R_fixture 50.000, V_fixture 0.0: 20-80 % time 400ps typ, 450ps min, 379ps max; typ from 0 V to 0.696 V
|   rising waveform, R_fixture 50.000, V_fixture 2.500: 20-80 % time 264ps typ, 359ps min, 187ps max; typ from 1.74 V to 2.5 V
|   falling waveform, R_fixture 50.000, V_fixture 2.500: 20-80 % time 491ps typ, 507ps min, 480ps max; typ from 2.5 V to 1.74 V
|   falling waveform, R_fixture 50.000, V_fixture 0.0: 20-80 % time 236ps typ, 319ps min, 175ps max; typ from 0.696 V to 0 V
[Pulldown]
|Voltage   I(typ)   I(min)   I(max)
-2.5V     -13.08mA   -7.815mA   -20.75mA
-904mV    -13.08mA   -7.815mA   -20.75mA
-752mV    -13.08mA   -7.815mA   -18.92mA
-524mV    -10.41mA   -7.109mA   -15.34mA
312mV     5.902mA    3.803mA    9.102mA
616mV     10.18mA    6.553mA    15.68mA
844mV     12.43mA    8.006mA    19.04mA
1.452V    14.89mA    9.697mA    22.3mA
3.124V    16.15mA    10.73mA    23.85mA
3.58V     17.45mA    11.25mA    24.92mA
4.112V    20.33mA    11.72mA    30.12mA
5V        24.74mA    11.73mA    44.56mA
[Pullup]
|Voltage   I(typ)   I(min)   I(max)
-2.5V     50.77mA    37.13mA    82.66mA
-2.068V   41.29mA    30.47mA    66.28mA
-1.688V   33.27mA    24.69mA    52.73mA
-700mV    13.63mA    10.07mA    20.84mA
-168mV    3.057mA    2.23mA     4.86mA
136mV     -2.284mA   -1.64mA    -3.687mA
440mV     -6.588mA   -4.693mA   -10.74mA
744mV     -9.822mA   -6.926mA   -16.19mA
1.124V    -12.43mA   -8.62mA    -20.86mA
1.58V     -13.68mA   -9.308mA   -23.56mA
2.72V     -14.62mA   -9.887mA   -25.54mA
5V        -15.96mA   -10.7mA    -28.06mA
[GND_clamp]
|Voltage   I(typ)   I(min)   I(max)
-2.5V     -3.262A    -2.545A    -4.485A
-1.123V   -498.5mA   -505.1mA   -498.3mA
-1.072V   -406.1mA   -436mA     -369.4mA
-1.021V   -317.1mA   -368.7mA   -251mA
-970mV    -233.3mA   -303.5mA   -153.4mA
-919mV    -157.7mA   -241.1mA   -95.21mA
-868mV    -95.78mA   -182.7mA   -74.26mA
-817mV    -55.48mA   -129.4mA   -63.96mA
-715mV    -26.89mA   -46.57mA   -42.82mA
-562mV    -8.195mA   -4.484mA   -13.98mA
-358mV    -153.4uA   -68.26uA   -250.2uA
2.5V      0A         0A         0A
[POWER_clamp]
|Voltage   I(typ)   I(min)   I(max)
-2.5V     54.23mA    42.85mA    83.47mA
-2.039V   41.12mA    31.42mA    65.66mA
-1.784V   33.99mA    25.46mA    56.34mA
-1.121V   16.56mA    11.45mA    31.14mA
-917mV    11.31mA    7.645mA    22.57mA
-815mV    8.625mA    5.831mA    17.67mA
-611mV    2.953mA    2.495mA    5.465mA
-560mV    1.702mA    1.758mA    3.215mA
-509mV    833.1uA    1.093mA    1.608mA
-458mV    359uA      552.7uA    679.3uA
-254mV    7.444uA    6.928uA    15.57uA
2.5V      0A         0A         3.059nA
[Ramp]
| variable   typ   min   max
dV/dt_r   0.417/0.398n   0.285/0.445n   0.695/0.379n
dV/dt_f   0.459/0.490n   0.303/0.514n   0.673/0.475n
R_load = 50.000
[Rising Waveform]
R_fixture= 50.000
V_fixture= 0.0
V_fixture_min= 0.0
V_fixture_max= 0.0
|time   V(typ)   V(min)   V(max)
0s        15.97nV    95.27nV    53nV
597ps     -211.5uV   12.22uV    -12.15mV
811ps     -1.403mV   12.22uV    640.7mV
1.036ns   -20.2mV    -63.76uV   912.9mV
1.418ns   482.7mV    -3.106mV   1.06V
1.73ns    608.7mV    -11.26mV   1.106V
1.976ns   644.1mV    205mV      1.127V
2.393ns   671.3mV    400.7mV    1.145V
3.315ns   690.5mV    465.5mV    1.156V
20ns      695.7mV    475.2mV    1.159V
[Rising Waveform]
R_fixture= 50.000
V_fixture= 2.500
V_fixture_min= 2.380
V_fixture_max= 2.630
|time   V(typ)   V(min)   V(max)
0s        1.736V     1.876V     1.508V
531ps     1.736V     1.876V     1.509V
720ps     1.735V     1.876V     2.283V
904ps     1.734V     1.876V     2.499V
1.223ns   2.317V     1.876V     2.574V
1.463ns   2.424V     1.875V     2.598V
1.598ns   2.442V     2V         2.606V
1.953ns   2.466V     2.288V     2.619V
2.526ns   2.486V     2.352V     2.627V
20ns      2.5V       2.38V      2.63V
[Falling Waveform]
R_fixture= 50.000
V_fixture= 2.500
V_fixture_min= 2.380
V_fixture_max= 2.630
|time   V(typ)   V(min)   V(max)
0s        2.5V       2.38V      2.63V
614ps     2.499V     2.38V      2.653V
830ps     2.499V     2.38V      2.049V
1.082ns   2.526V     2.379V     1.783V
1.313ns   2.149V     2.379V     1.678V
1.51ns    1.966V     2.379V     1.628V
1.874ns   1.845V     2.399V     1.564V
2.309ns   1.792V     2.045V     1.53V
3.783ns   1.743V     1.898V     1.509V
20ns      1.736V     1.876V     1.508V
[Falling Waveform]
R_fixture= 50.000
V_fixture= 0.0
V_fixture_min= 0.0
V_fixture_max= 0.0
|time   V(typ)   V(min)   V(max)
0s        695.7mV    475.1mV    1.159V
572ps     694.9mV    475mV      1.15V
710ps     694.6mV    475.1mV    489.9mV
804ps     694.6mV    475mV      235.1mV
1.027ns   668.3mV    474.5mV    71.24mV
1.397ns   95.38mV    474.7mV    21.32mV
1.714ns   30.99mV    464.5mV    8.749mV
2.214ns   10.02mV    67.49mV    2.31mV
2.976ns   2.339mV    10.42mV    318.9uV
20ns      -32.02nV   -55.69nV   -36.95nV
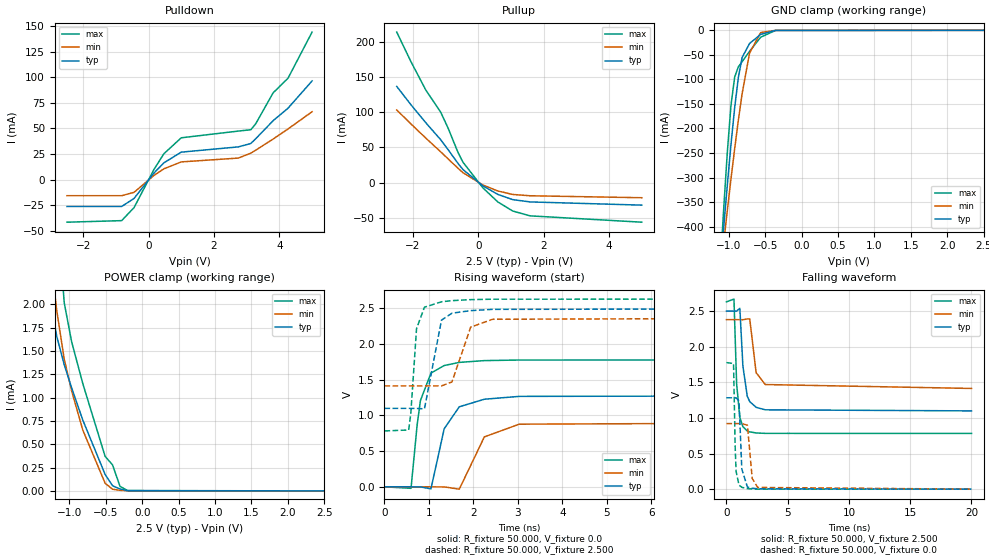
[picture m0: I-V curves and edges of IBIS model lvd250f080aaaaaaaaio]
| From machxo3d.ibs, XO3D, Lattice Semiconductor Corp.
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|   Model lvd250f080aaaaaaaaio
[Model] lvd250f080aaaaaaaaio
Model_type I/O
Polarity   Non-Inverting
Enable   Active-Low
Vinl =  0.700V
Vinh =  1.700V
Vmeas =  1.250V
Cref =  0.0F
Rref =  1.000M
Vref =  0.0V
C_comp   4.200pF   3.800pF   7.500pF
[Temperature Range]   25.000   0.105k   -40.000
[Voltage Range]   2.500V   2.380V   2.630V
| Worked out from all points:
|   slope of the pulldown table from 0 to 0.375 V, typ, clamps not added: 27.2 ohm
|   slope of the pullup table from 0 to 0.375 V, typ, clamps not added: 32.5 ohm
|   GND clamp passes 1 mA (typ) near -0.43 V on its own axis
|   POWER clamp passes 1 mA (typ) near -0.92 V on its own axis
|   rising waveform, R_fixture 50.000, V_fixture 0.0: 20-80 % time 368ps typ, 453ps min, 223ps max; typ from 0 V to 1.28 V
|   rising waveform, R_fixture 50.000, V_fixture 2.500: 20-80 % time 205ps typ, 303ps min, 127ps max; typ from 1.1 V to 2.5 V
|   falling waveform, R_fixture 50.000, V_fixture 2.500: 20-80 % time 393ps typ, 472ps min, 286ps max; typ from 2.5 V to 1.1 V
|   falling waveform, R_fixture 50.000, V_fixture 0.0: 20-80 % time 180ps typ, 266ps min, 123ps max; typ from 1.28 V to 0 V
[Pulldown]
|Voltage   I(typ)   I(min)   I(max)
-2.5V     -26.15mA   -15.63mA   -41.49mA
-828mV    -26.15mA   -15.63mA   -39.97mA
-448mV    -18.28mA   -12.33mA   -27.2mA
160mV     6.444mA    4.153mA    9.94mA
464mV     16.44mA    10.59mA    25.34mA
996mV     26.9mA     17.37mA    40.9mA
2.744V    32.03mA    21.11mA    47.47mA
3.124V    35.33mA    25.9mA     48.76mA
3.276V    40.02mA    28.82mA    54.65mA
3.808V    57.59mA    39.69mA    84.8mA
4.264V    69.81mA    49.54mA    99.08mA
5V        96.41mA    66.35mA    144.1mA
[Pullup]
|Voltage   I(typ)   I(min)   I(max)
-2.5V     136.5mA    103.1mA    213.6mA
-2.068V   110.7mA    83.44mA    171.9mA
-1.612V   85.07mA    63.25mA    131.5mA
-1.156V   60.96mA    43.79mA    100.1mA
-928mV    46.77mA    33.7mA     77.35mA
-624mV    27.23mA    20.38mA    42.78mA
-472mV    18.53mA    14.06mA    28.92mA
136mV     -4.568mA   -3.281mA   -7.374mA
592mV     -16.67mA   -11.82mA   -27.32mA
1.048V    -24.06mA   -16.75mA   -40.22mA
1.58V     -27.35mA   -18.62mA   -47.12mA
5V        -31.91mA   -21.4mA    -56.11mA
[GND_clamp]
|Voltage   I(typ)   I(min)   I(max)
-2.5V     -3.262A    -2.545A    -4.485A
-1.123V   -498.5mA   -505.1mA   -498.3mA
-1.072V   -406.1mA   -436mA     -369.4mA
-1.021V   -317.1mA   -368.7mA   -251mA
-970mV    -233.3mA   -303.5mA   -153.4mA
-919mV    -157.7mA   -241.1mA   -95.21mA
-868mV    -95.78mA   -182.7mA   -74.26mA
-817mV    -55.48mA   -129.4mA   -63.96mA
-715mV    -26.89mA   -46.57mA   -42.82mA
-562mV    -8.195mA   -4.484mA   -13.98mA
-358mV    -153.4uA   -68.26uA   -250.2uA
2.5V      0A         0A         0A
[POWER_clamp]
|Voltage   I(typ)   I(min)   I(max)
-2.5V     19.37mA    14.08mA    35.47mA
-1.274V   2.185mA    2.634mA    5.424mA
-1.223V   1.865mA    2.265mA    4.051mA
-1.172V   1.654mA    1.93mA     3.052mA
-1.07V    1.353mA    1.412mA    2.016mA
-968mV    1.104mA    1.071mA    1.597mA
-815mV    758.5uA    651.8uA    1.15mA
-509mV    176.7uA    82.75uA    370.5uA
-407mV    55.24uA    18.01uA    278.8uA
-305mV    21.57uA    6.5uA      49.89uA
-203mV    2.401uA    2.25uA     4.21uA
2.5V      0A         0A         3.059nA
[Ramp]
| variable   typ   min   max
dV/dt_r   0.770/0.368n   0.553/0.453n   1.066/0.227n
dV/dt_f   0.841/0.393n   0.579/0.463n   1.108/0.285n
R_load = 50.000
[Rising Waveform]
R_fixture= 50.000
V_fixture= 0.0
V_fixture_min= 0.0
V_fixture_max= 0.0
|time   V(typ)   V(min)   V(max)
0s        10.53nV    67.7nV     32.65nV
597ps     -252.8uV   6.154uV    -20.86mV
735ps     -630.2uV   6.154uV    870.1mV
809ps     -1.286mV   6.154uV    1.21V
1.045ns   -28.5mV    -361.4uV   1.593V
1.343ns   814mV      -984.8uV   1.699V
1.682ns   1.121V     -32.73mV   1.743V
2.246ns   1.227V     699.6mV    1.768V
3.031ns   1.267V     877.6mV    1.776V
20ns      1.283V     921.3mV    1.777V
[Rising Waveform]
R_fixture= 50.000
V_fixture= 2.500
V_fixture_min= 2.380
V_fixture_max= 2.630
|time   V(typ)   V(min)   V(max)
0s        1.099V     1.414V     783mV
544ps     1.099V     1.414V     796mV
592ps     1.099V     1.414V     1.026V
721ps     1.098V     1.414V     2.216V
899ps     1.092V     1.414V     2.516V
1.282ns   2.335V     1.414V     2.592V
1.517ns   2.432V     1.469V     2.608V
1.939ns   2.468V     2.237V     2.622V
2.431ns   2.486V     2.347V     2.628V
20ns      2.5V       2.38V      2.63V
[Falling Waveform]
R_fixture= 50.000
V_fixture= 2.500
V_fixture_min= 2.380
V_fixture_max= 2.630
|time   V(typ)   V(min)   V(max)
0s        2.5V       2.38V      2.63V
613ps     2.499V     2.38V      2.669V
832ps     2.5V       2.38V      1.476V
1.094ns   2.538V     2.379V     1.004V
1.344ns   1.725V     2.379V     878.2mV
1.699ns   1.305V     2.39V      816.4mV
1.901ns   1.229V     2.391V     804.3mV
2.423ns   1.149V     1.635V     789.2mV
3.168ns   1.114V     1.469V     783.4mV
20ns      1.099V     1.414V     783mV
[Falling Waveform]
R_fixture= 50.000
V_fixture= 0.0
V_fixture_min= 0.0
V_fixture_max= 0.0
|time   V(typ)   V(min)   V(max)
0s        1.283V     921.3mV    1.777V
579ps     1.282V     921.2mV    1.765V
710ps     1.282V     921.3mV    607.4mV
788ps     1.282V     921.2mV    250.5mV
1.024ns   1.24V      920.8mV    58.04mV
1.254ns   283.3mV    921mV      26.11mV
1.711ns   29.33mV    897.9mV    7.246mV
2.103ns   13.24mV    150.6mV    2.488mV
2.552ns   5.427mV    24.32mV    676.1uV
20ns      -65.56nV   22.28nV    74.4nV
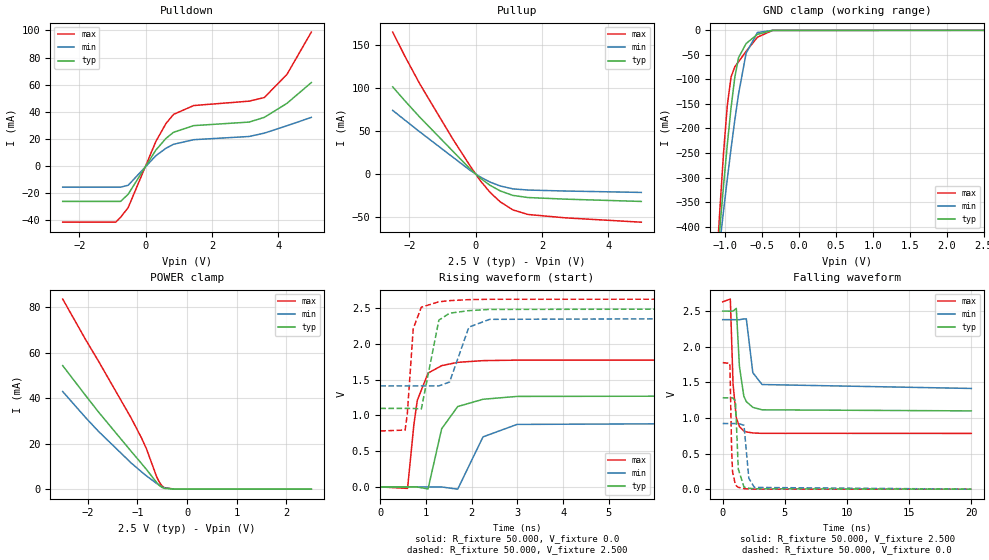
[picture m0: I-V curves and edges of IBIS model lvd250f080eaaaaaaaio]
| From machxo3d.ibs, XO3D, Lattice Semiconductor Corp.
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|   Model lvd250f080eaaaaaaaio
[Model] lvd250f080eaaaaaaaio
Model_type I/O
Polarity   Non-Inverting
Enable   Active-Low
Vinl =  0.700V
Vinh =  1.700V
Vmeas =  1.250V
Cref =  0.0F
Rref =  1.000M
Vref =  0.0V
C_comp   4.200pF   3.800pF   7.500pF
[Temperature Range]   25.000   0.105k   -40.000
[Voltage Range]   2.500V   2.380V   2.630V
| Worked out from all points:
|   slope of the pulldown table from 0 to 0.375 V, typ, clamps not added: 27.2 ohm
|   slope of the pullup table from 0 to 0.375 V, typ, clamps not added: 32.5 ohm
|   GND clamp passes 1 mA (typ) near -0.43 V on its own axis
|   POWER clamp passes 1 mA (typ) near -0.52 V on its own axis
|   rising waveform, R_fixture 50.000, V_fixture 0.0: 20-80 % time 367ps typ, 457ps min, 225ps max; typ from 0 V to 1.28 V
|   rising waveform, R_fixture 50.000, V_fixture 2.500: 20-80 % time 205ps typ, 303ps min, 127ps max; typ from 1.1 V to 2.5 V
|   falling waveform, R_fixture 50.000, V_fixture 2.500: 20-80 % time 393ps typ, 472ps min, 286ps max; typ from 2.5 V to 1.1 V
|   falling waveform, R_fixture 50.000, V_fixture 0.0: 20-80 % time 180ps typ, 266ps min, 123ps max; typ from 1.28 V to 0 V
[Pulldown]
|Voltage   I(typ)   I(min)   I(max)
-2.5V     -26.15mA   -15.63mA   -41.49mA
-904mV    -26.15mA   -15.63mA   -41.49mA
-752mV    -26.15mA   -15.63mA   -37.84mA
-524mV    -20.82mA   -14.22mA   -30.68mA
312mV     11.8mA     7.606mA    18.2mA
616mV     20.36mA    13.11mA    31.35mA
844mV     24.87mA    16.01mA    38.07mA
1.452V    29.78mA    19.39mA    44.59mA
3.124V    32.39mA    21.76mA    47.83mA
3.58V     35.84mA    24.22mA    50.47mA
4.264V    46.19mA    29.69mA    67.54mA
5V        61.55mA    35.85mA    98.8mA
[Pullup]
|Voltage   I(typ)   I(min)   I(max)
-2.5V     101.7mA    74.29mA    165.6mA
-2.144V   85.94mA    63.3mA     138.3mA
-1.688V   66.57mA    49.39mA    105.5mA
-700mV    27.27mA    20.14mA    41.68mA
-168mV    6.114mA    4.46mA     9.719mA
136mV     -4.568mA   -3.281mA   -7.374mA
440mV     -13.18mA   -9.386mA   -21.47mA
744mV     -19.64mA   -13.85mA   -32.38mA
1.124V    -24.85mA   -17.24mA   -41.72mA
1.58V     -27.35mA   -18.62mA   -47.12mA
2.72V     -29.25mA   -19.77mA   -51.08mA
5V        -31.91mA   -21.4mA    -56.11mA
[GND_clamp]
|Voltage   I(typ)   I(min)   I(max)
-2.5V     -3.262A    -2.545A    -4.485A
-1.123V   -498.5mA   -505.1mA   -498.3mA
-1.072V   -406.1mA   -436mA     -369.4mA
-1.021V   -317.1mA   -368.7mA   -251mA
-970mV    -233.3mA   -303.5mA   -153.4mA
-919mV    -157.7mA   -241.1mA   -95.21mA
-868mV    -95.78mA   -182.7mA   -74.26mA
-817mV    -55.48mA   -129.4mA   -63.96mA
-715mV    -26.89mA   -46.57mA   -42.82mA
-562mV    -8.195mA   -4.484mA   -13.98mA
-358mV    -153.4uA   -68.26uA   -250.2uA
2.5V      0A         0A         0A
[POWER_clamp]
|Voltage   I(typ)   I(min)   I(max)
-2.5V     54.23mA    42.85mA    83.47mA
-2.039V   41.12mA    31.42mA    65.66mA
-1.784V   33.99mA    25.46mA    56.34mA
-1.121V   16.56mA    11.45mA    31.14mA
-917mV    11.31mA    7.645mA    22.57mA
-815mV    8.625mA    5.831mA    17.67mA
-611mV    2.953mA    2.495mA    5.465mA
-560mV    1.702mA    1.758mA    3.215mA
-509mV    833.1uA    1.093mA    1.608mA
-458mV    359uA      552.7uA    679.3uA
-254mV    7.444uA    6.927uA    15.57uA
2.5V      0A         0A         3.059nA
[Ramp]
| variable   typ   min   max
dV/dt_r   0.770/0.368n   0.553/0.454n   1.066/0.227n
dV/dt_f   0.841/0.393n   0.579/0.463n   1.108/0.285n
R_load = 50.000
[Rising Waveform]
R_fixture= 50.000
V_fixture= 0.0
V_fixture_min= 0.0
V_fixture_max= 0.0
|time   V(typ)   V(min)   V(max)
0s        10.52nV    67.5nV     32.65nV
597ps     -252.8uV   6.15uV     -20.86mV
735ps     -630.2uV   6.15uV     870.1mV
809ps     -1.286mV   6.15uV     1.21V
1.045ns   -28.5mV    -361.5uV   1.593V
1.343ns   814mV      -985.2uV   1.698V
1.694ns   1.125V     -31.64mV   1.744V
2.248ns   1.227V     700.5mV    1.768V
2.992ns   1.267V     874.8mV    1.775V
20ns      1.283V     921.3mV    1.777V
[Rising Waveform]
R_fixture= 50.000
V_fixture= 2.500
V_fixture_min= 2.380
V_fixture_max= 2.630
|time   V(typ)   V(min)   V(max)
0s        1.099V     1.414V     783mV
544ps     1.099V     1.414V     796mV
592ps     1.099V     1.414V     1.026V
721ps     1.098V     1.414V     2.216V
899ps     1.092V     1.414V     2.516V
1.282ns   2.335V     1.414V     2.592V
1.517ns   2.432V     1.469V     2.608V
1.939ns   2.468V     2.237V     2.622V
2.392ns   2.485V     2.346V     2.627V
20ns      2.5V       2.38V      2.63V
[Falling Waveform]
R_fixture= 50.000
V_fixture= 2.500
V_fixture_min= 2.380
V_fixture_max= 2.630
|time   V(typ)   V(min)   V(max)
0s        2.5V       2.38V      2.63V
613ps     2.499V     2.38V      2.669V
832ps     2.5V       2.38V      1.476V
1.094ns   2.538V     2.379V     1.004V
1.344ns   1.725V     2.379V     878.2mV
1.699ns   1.305V     2.39V      816.4mV
1.901ns   1.229V     2.391V     804.3mV
2.423ns   1.149V     1.635V     789.2mV
3.168ns   1.114V     1.469V     783.4mV
20ns      1.099V     1.414V     783mV
[Falling Waveform]
R_fixture= 50.000
V_fixture= 0.0
V_fixture_min= 0.0
V_fixture_max= 0.0
|time   V(typ)   V(min)   V(max)
0s        1.283V     921.3mV    1.777V
579ps     1.282V     921.2mV    1.765V
710ps     1.282V     921.3mV    607.4mV
788ps     1.282V     921.2mV    250.5mV
1.024ns   1.24V      920.8mV    58.04mV
1.254ns   283.3mV    921mV      26.11mV
1.711ns   29.33mV    897.9mV    7.246mV
2.103ns   13.24mV    150.6mV    2.488mV
2.552ns   5.427mV    24.32mV    676.1uV
20ns      -65.56nV   22.28nV    74.4nV
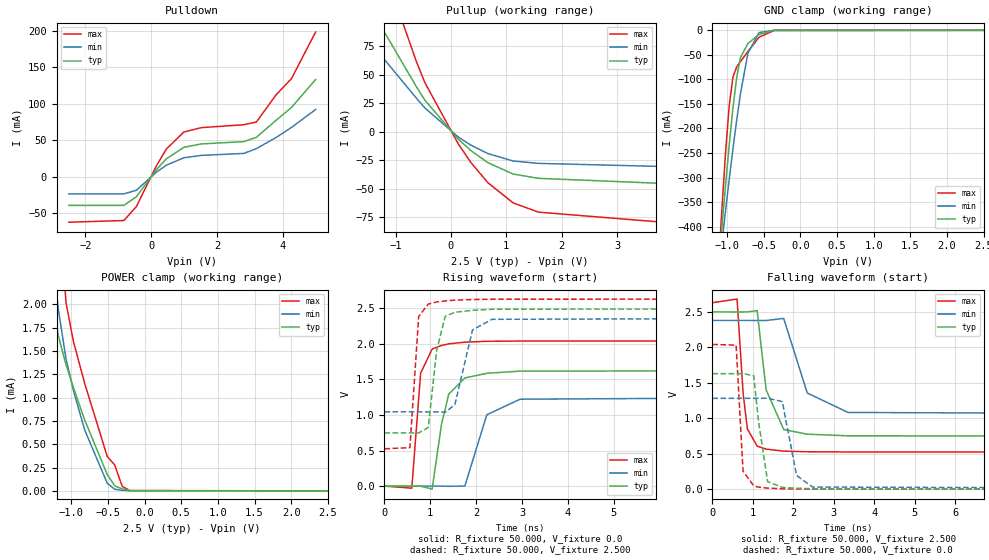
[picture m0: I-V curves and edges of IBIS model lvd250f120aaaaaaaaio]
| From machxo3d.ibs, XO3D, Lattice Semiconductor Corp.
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|   Model lvd250f120aaaaaaaaio
[Model] lvd250f120aaaaaaaaio
Model_type I/O
Polarity   Non-Inverting
Enable   Active-Low
Vinl =  0.700V
Vinh =  1.700V
Vmeas =  1.250V
Cref =  0.0F
Rref =  1.000M
Vref =  0.0V
C_comp   4.200pF   3.800pF   7.500pF
[Temperature Range]   25.000   0.105k   -40.000
[Voltage Range]   2.500V   2.380V   2.630V
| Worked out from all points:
|   slope of the pulldown table from 0 to 0.375 V, typ, clamps not added: 18.1 ohm
|   slope of the pullup table from 0 to 0.375 V, typ, clamps not added: 21.7 ohm
|   GND clamp passes 1 mA (typ) near -0.43 V on its own axis
|   POWER clamp passes 1 mA (typ) near -0.92 V on its own axis
|   rising waveform, R_fixture 50.000, V_fixture 0.0: 20-80 % time 272ps typ, 407ps min, 149ps max; typ from 0 V to 1.63 V
|   rising waveform, R_fixture 50.000, V_fixture 2.500: 20-80 % time 174ps typ, 280ps min, 98.3ps max; typ from 0.747 V to 2.5 V
|   falling waveform, R_fixture 50.000, V_fixture 2.500: 20-80 % time 267ps typ, 393ps min, 161ps max; typ from 2.5 V to 0.747 V
|   falling waveform, R_fixture 50.000, V_fixture 0.0: 20-80 % time 147ps typ, 237ps min, 94.5ps max; typ from 1.63 V to 0 V
[Pulldown]
|Voltage   I(typ)   I(min)   I(max)
-2.5V     -39.23mA   -23.44mA   -62.24mA
-828mV    -39.23mA   -23.44mA   -59.96mA
-448mV    -27.42mA   -18.49mA   -40.8mA
160mV     9.666mA    6.229mA    14.91mA
464mV     24.66mA    15.88mA    38.02mA
996mV     40.36mA    26.05mA    61.35mA
1.528V    45.04mA    29.35mA    67.36mA
2.82V     48.16mA    32.01mA    71.35mA
3.2V      54.04mA    38.6mA     75.05mA
3.808V    77.75mA    54.06mA    112.8mA
4.264V    94.88mA    67.53mA    134.3mA
5V        133.2mA    92.12mA    198.3mA
[Pullup]
|Voltage   I(typ)   I(min)   I(max)
-2.5V     187.6mA    140.3mA    296.9mA
-2.068V   152.2mA    114mA      238.5mA
-1.612V   116.8mA    86.82mA    181.7mA
-1.156V   83.54mA    60.54mA    135.3mA
-624mV    39.38mA    29.34mA    61.43mA
-472mV    27.62mA    20.78mA    43.09mA
136mV     -6.852mA   -4.921mA   -11.06mA
364mV     -16.84mA   -12.02mA   -27.38mA
668mV     -27.33mA   -19.33mA   -44.92mA
1.124V    -37.28mA   -25.86mA   -62.59mA
1.58V     -41.03mA   -27.92mA   -70.68mA
5V        -47.87mA   -32.1mA    -84.17mA
[GND_clamp]
|Voltage   I(typ)   I(min)   I(max)
-2.5V     -3.262A    -2.545A    -4.485A
-1.123V   -498.5mA   -505.1mA   -498.3mA
-1.072V   -406.1mA   -436mA     -369.4mA
-1.021V   -317.1mA   -368.7mA   -251mA
-970mV    -233.3mA   -303.5mA   -153.4mA
-919mV    -157.7mA   -241.1mA   -95.21mA
-868mV    -95.78mA   -182.7mA   -74.26mA
-817mV    -55.48mA   -129.4mA   -63.96mA
-715mV    -26.89mA   -46.57mA   -42.82mA
-562mV    -8.195mA   -4.484mA   -13.98mA
-358mV    -153.4uA   -68.26uA   -250.2uA
2.5V      0A         0A         0A
[POWER_clamp]
|Voltage   I(typ)   I(min)   I(max)
-2.5V     19.37mA    14.08mA    35.47mA
-1.274V   2.185mA    2.634mA    5.424mA
-1.223V   1.865mA    2.265mA    4.051mA
-1.172V   1.654mA    1.93mA     3.052mA
-1.07V    1.353mA    1.412mA    2.016mA
-968mV    1.104mA    1.071mA    1.597mA
-815mV    758.5uA    651.8uA    1.15mA
-509mV    176.7uA    82.75uA    370.5uA
-407mV    55.24uA    18.01uA    278.8uA
-305mV    21.57uA    6.5uA      49.89uA
-203mV    2.401uA    2.25uA     4.21uA
2.5V      0A         0A         3.059nA
[Ramp]
| variable   typ   min   max
dV/dt_r   0.978/0.271n   0.769/0.403n   1.225/0.148n
dV/dt_f   1.052/0.267n   0.801/0.394n   1.263/0.166n
R_load = 50.000
[Rising Waveform]
R_fixture= 50.000
V_fixture= 0.0
V_fixture_min= 0.0
V_fixture_max= 0.0
|time   V(typ)   V(min)   V(max)
0s        7.849nV    52.34nV    23.59nV
596ps     -189.4uV   2.388uV    -29.45mV
789ps     -945.9uV   2.388uV    1.588V
1.039ns   -43.33mV   -253.5uV   1.927V
1.243ns   867.2mV    -517.1uV   1.978V
1.401ns   1.292V     -3.551mV   2V
1.752ns   1.521V     201uV      2.024V
2.231ns   1.586V     1.003V     2.036V
2.957ns   1.617V     1.222V     2.04V
20ns      1.629V     1.281V     2.041V
[Rising Waveform]
R_fixture= 50.000
V_fixture= 2.500
V_fixture_min= 2.380
V_fixture_max= 2.630
|time   V(typ)   V(min)   V(max)
0s        747.2mV    1.044V     524.3mV
555ps     747.1mV    1.045V     540.6mV
746ps     746.9mV    1.044V     2.385V
955ps     823.9mV    1.044V     2.56V
1.138ns   1.909V     1.044V     2.589V
1.326ns   2.388V     1.039V     2.604V
1.534ns   2.444V     1.144V     2.615V
1.92ns    2.472V     2.197V     2.624V
2.344ns   2.487V     2.345V     2.628V
20ns      2.5V       2.38V      2.63V
[Falling Waveform]
R_fixture= 50.000
V_fixture= 2.500
V_fixture_min= 2.380
V_fixture_max= 2.630
|time   V(typ)   V(min)   V(max)
0s        2.5V       2.38V      2.63V
610ps     2.499V     2.38V      2.681V
761ps     2.499V     2.38V      1.347V
865ps     2.5V       2.38V      849.7mV
1.106ns   2.518V     2.379V     606.7mV
1.328ns   1.401V     2.379V     564.8mV
1.763ns   842mV      2.408V     536.5mV
2.345ns   775.3mV    1.356V     527.5mV
3.353ns   752.2mV    1.082V     524.5mV
20ns      747.2mV    1.044V     524.3mV
[Falling Waveform]
R_fixture= 50.000
V_fixture= 0.0
V_fixture_min= 0.0
V_fixture_max= 0.0
|time   V(typ)   V(min)   V(max)
0s        1.629V     1.281V     2.041V
587ps     1.629V     1.281V     2.031V
759ps     1.629V     1.281V     254.4mV
1.022ns   1.6V       1.281V     45.38mV
1.14ns    957.8mV    1.281V     29.02mV
1.366ns   106.4mV    1.282V     14.53mV
1.728ns   25.16mV    1.235V     5.61mV
2.082ns   12.34mV    193.3mV    1.835mV
2.475ns   5.716mV    29.92mV    648.3uV
20ns      -256.3nV   -1.986nV   -79.61nV
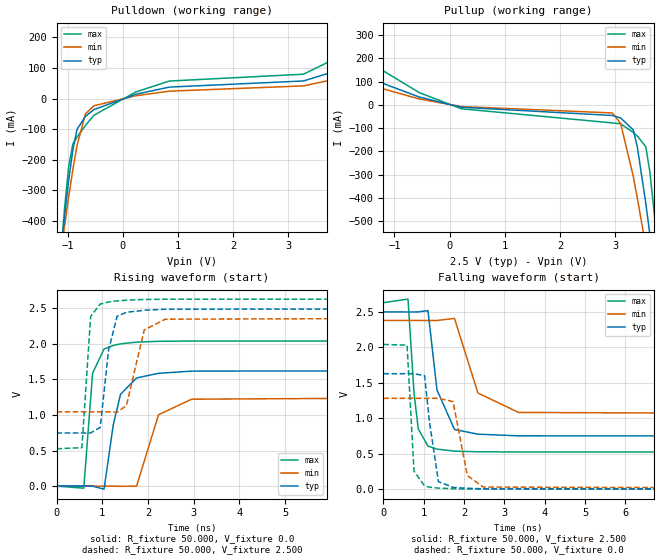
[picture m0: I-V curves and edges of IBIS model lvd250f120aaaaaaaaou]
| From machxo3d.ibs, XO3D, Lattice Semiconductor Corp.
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|   Model lvd250f120aaaaaaaaou
[Model] lvd250f120aaaaaaaaou
Model_type Output
Polarity   Non-Inverting
Enable   Active-High
Vmeas =  1.250V
Cref =  0.0F
Rref =  1.000M
Vref =  0.0V
C_comp   4.200pF   3.800pF   7.500pF
[Temperature Range]   25.000   0.105k   -40.000
[Voltage Range]   2.500V   2.380V   2.630V
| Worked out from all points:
|   slope of the pulldown table from 0 to 0.375 V, typ, clamps not added: 18.1 ohm
|   slope of the pullup table from 0 to 0.375 V, typ, clamps not added: 21.7 ohm
|   rising waveform, R_fixture 50.000, V_fixture 0.0: 20-80 % time 272ps typ, 407ps min, 149ps max; typ from 0 V to 1.63 V
|   rising waveform, R_fixture 50.000, V_fixture 2.500: 20-80 % time 174ps typ, 278ps min, 98.3ps max; typ from 0.747 V to 2.5 V
|   falling waveform, R_fixture 50.000, V_fixture 2.500: 20-80 % time 267ps typ, 393ps min, 161ps max; typ from 2.5 V to 0.747 V
|   falling waveform, R_fixture 50.000, V_fixture 0.0: 20-80 % time 147ps typ, 237ps min, 94.5ps max; typ from 1.63 V to 0 V
[Pulldown]
|Voltage   I(typ)   I(min)   I(max)
-2.5V     -3.263A    -2.546A    -4.486A
-1.132V   -522.1mA   -521mA     -536.8mA
-1.056V   -388.2mA   -419.1mA   -361.5mA
-980mV    -267.1mA   -321.9mA   -222.8mA
-904mV    -167.6mA   -231.8mA   -148.7mA
-828mV    -100.6mA   -153.1mA   -126mA
-676mV    -58.31mA   -50.11mA   -88.3mA
-524mV    -36.34mA   -23.73mA   -54.82mA
236mV     13.82mA    8.909mA    21.32mA
844mV     37.3mA     24.02mA    57.11mA
3.276V    57.4mA     41.23mA    79.45mA
5V        152.5mA    107.6mA    231.4mA
[Pullup]
|Voltage   I(typ)   I(min)   I(max)
-2.5V     207mA      154.4mA    332.4mA
-548mV    33.39mA    25.12mA    52.14mA
212mV     -10.39mA   -7.447mA   -16.81mA
2.948V    -45.68mA   -34.89mA   -77.59mA
3.1V      -56.59mA   -79.82mA   -81.6mA
3.328V    -107.2mA   -306.6mA   -118.1mA
3.404V    -183mA     -403.1mA   -134.6mA
3.556V    -423.3mA   -609mA     -180.1mA
3.632V    -560.8mA   -715.9mA   -291.3mA
3.708V    -703.4mA   -824.4mA   -464.4mA
3.784V    -849.3mA   -934.3mA   -660.2mA
5V        -3.31A     -2.76A     -4.184A
[Ramp]
| variable   typ   min   max
dV/dt_r   0.978/0.271n   0.769/0.403n   1.225/0.148n
dV/dt_f   1.052/0.267n   0.801/0.394n   1.263/0.166n
R_load = 50.000
[Rising Waveform]
R_fixture= 50.000
V_fixture= 0.0
V_fixture_min= 0.0
V_fixture_max= 0.0
|time   V(typ)   V(min)   V(max)
0s        7.849nV    52.34nV    23.59nV
596ps     -189.4uV   2.387uV    -29.45mV
789ps     -945.9uV   2.387uV    1.588V
1.039ns   -43.33mV   -253.4uV   1.927V
1.243ns   867.2mV    -517.1uV   1.978V
1.401ns   1.292V     -3.62mV    2V
1.752ns   1.521V     201uV      2.024V
2.231ns   1.586V     1.003V     2.036V
2.957ns   1.617V     1.222V     2.04V
20ns      1.629V     1.281V     2.041V
[Rising Waveform]
R_fixture= 50.000
V_fixture= 2.500
V_fixture_min= 2.380
V_fixture_max= 2.630
|time   V(typ)   V(min)   V(max)
0s        747.2mV    1.044V     524.3mV
555ps     747.1mV    1.045V     540.6mV
746ps     746.9mV    1.044V     2.385V
955ps     823.9mV    1.044V     2.56V
1.138ns   1.909V     1.044V     2.589V
1.326ns   2.388V     1.039V     2.604V
1.529ns   2.444V     1.132V     2.615V
1.918ns   2.472V     2.195V     2.624V
2.377ns   2.487V     2.347V     2.628V
20ns      2.5V       2.38V      2.63V
[Falling Waveform]
R_fixture= 50.000
V_fixture= 2.500
V_fixture_min= 2.380
V_fixture_max= 2.630
|time   V(typ)   V(min)   V(max)
0s        2.5V       2.38V      2.63V
610ps     2.499V     2.38V      2.681V
761ps     2.499V     2.38V      1.347V
865ps     2.5V       2.38V      849.7mV
1.106ns   2.518V     2.379V     606.7mV
1.328ns   1.401V     2.379V     564.8mV
1.763ns   842mV      2.408V     536.5mV
2.345ns   775.3mV    1.356V     527.5mV
3.353ns   752.2mV    1.082V     524.5mV
20ns      747.2mV    1.044V     524.3mV
[Falling Waveform]
R_fixture= 50.000
V_fixture= 0.0
V_fixture_min= 0.0
V_fixture_max= 0.0
|time   V(typ)   V(min)   V(max)
0s        1.629V     1.281V     2.041V
587ps     1.629V     1.281V     2.031V
759ps     1.629V     1.281V     254.4mV
1.022ns   1.6V       1.281V     45.38mV
1.14ns    957.8mV    1.281V     29.02mV
1.366ns   106.4mV    1.282V     14.53mV
1.728ns   25.16mV    1.235V     5.61mV
2.082ns   12.34mV    193.3mV    1.835mV
2.475ns   5.716mV    29.92mV    648.3uV
20ns      -256.3nV   -1.986nV   -79.61nV
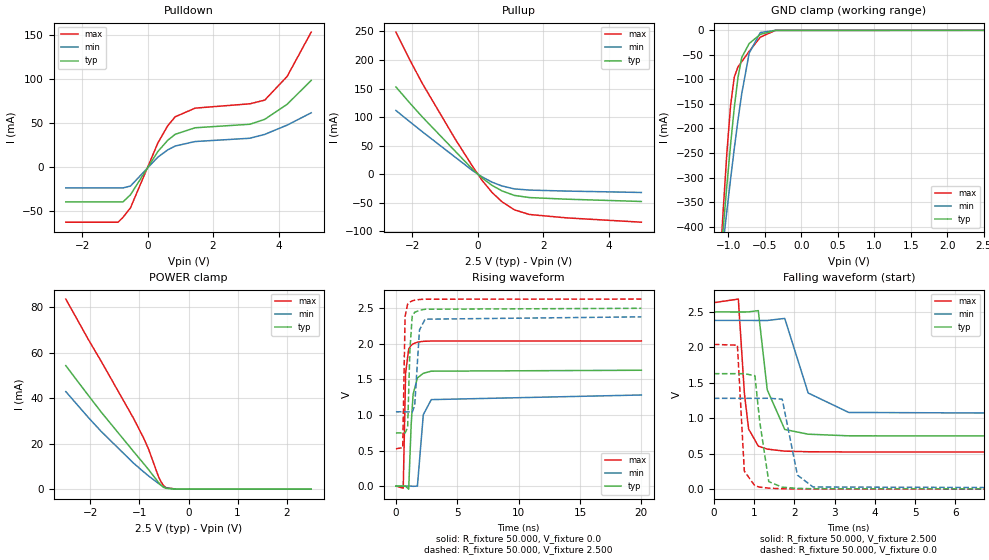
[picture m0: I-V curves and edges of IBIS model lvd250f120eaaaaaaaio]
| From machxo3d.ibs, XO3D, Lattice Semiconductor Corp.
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|   Model lvd250f120eaaaaaaaio
[Model] lvd250f120eaaaaaaaio
Model_type I/O
Polarity   Non-Inverting
Enable   Active-Low
Vinl =  0.700V
Vinh =  1.700V
Vmeas =  1.250V
Cref =  0.0F
Rref =  1.000M
Vref =  0.0V
C_comp   4.200pF   3.800pF   7.500pF
[Temperature Range]   25.000   0.105k   -40.000
[Voltage Range]   2.500V   2.380V   2.630V
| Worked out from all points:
|   slope of the pulldown table from 0 to 0.375 V, typ, clamps not added: 18.1 ohm
|   slope of the pullup table from 0 to 0.375 V, typ, clamps not added: 21.7 ohm
|   GND clamp passes 1 mA (typ) near -0.43 V on its own axis
|   POWER clamp passes 1 mA (typ) near -0.52 V on its own axis
|   rising waveform, R_fixture 50.000, V_fixture 0.0: 20-80 % time 272ps typ, 407ps min, 149ps max; typ from 0 V to 1.63 V
|   rising waveform, R_fixture 50.000, V_fixture 2.500: 20-80 % time 174ps typ, 278ps min, 98.3ps max; typ from 0.747 V to 2.5 V
|   falling waveform, R_fixture 50.000, V_fixture 2.500: 20-80 % time 267ps typ, 393ps min, 161ps max; typ from 2.5 V to 0.747 V
|   falling waveform, R_fixture 50.000, V_fixture 0.0: 20-80 % time 147ps typ, 236ps min, 94.5ps max; typ from 1.63 V to 0 V
[Pulldown]
|Voltage   I(typ)   I(min)   I(max)
-2.5V     -39.23mA   -23.44mA   -62.24mA
-904mV    -39.23mA   -23.44mA   -62.24mA
-752mV    -39.23mA   -23.44mA   -56.76mA
-524mV    -31.23mA   -21.33mA   -46.02mA
312mV     17.71mA    11.41mA    27.31mA
616mV     30.54mA    19.66mA    47.03mA
844mV     37.3mA     24.02mA    57.11mA
1.452V    44.67mA    29.09mA    66.89mA
3.124V    48.63mA    32.8mA     71.81mA
3.58V     54.23mA    37.19mA    76.01mA
4.264V    71.25mA    47.68mA    102.8mA
5V        98.32mA    61.62mA    153mA
[Pullup]
|Voltage   I(typ)   I(min)   I(max)
-2.5V     152.8mA    111.5mA    248.9mA
-2.068V   124.1mA    91.5mA     199.3mA
-1.688V   99.9mA     74.11mA    158.4mA
-700mV    40.9mA     30.22mA    62.53mA
-168mV    9.171mA    6.69mA     14.58mA
136mV     -6.852mA   -4.921mA   -11.06mA
440mV     -19.77mA   -14.08mA   -32.21mA
744mV     -29.47mA   -20.78mA   -48.57mA
1.124V    -37.28mA   -25.86mA   -62.59mA
1.58V     -41.03mA   -27.92mA   -70.68mA
2.72V     -43.87mA   -29.66mA   -76.62mA
5V        -47.87mA   -32.1mA    -84.17mA
[GND_clamp]
|Voltage   I(typ)   I(min)   I(max)
-2.5V     -3.262A    -2.545A    -4.485A
-1.123V   -498.5mA   -505.1mA   -498.3mA
-1.072V   -406.1mA   -436mA     -369.4mA
-1.021V   -317.1mA   -368.7mA   -251mA
-970mV    -233.3mA   -303.5mA   -153.4mA
-919mV    -157.7mA   -241.1mA   -95.21mA
-868mV    -95.78mA   -182.7mA   -74.26mA
-817mV    -55.48mA   -129.4mA   -63.96mA
-715mV    -26.89mA   -46.57mA   -42.82mA
-562mV    -8.195mA   -4.484mA   -13.98mA
-358mV    -153.4uA   -68.26uA   -250.2uA
2.5V      0A         0A         0A
[POWER_clamp]
|Voltage   I(typ)   I(min)   I(max)
-2.5V     54.23mA    42.85mA    83.47mA
-2.039V   41.12mA    31.42mA    65.66mA
-1.784V   33.99mA    25.46mA    56.34mA
-1.121V   16.56mA    11.45mA    31.14mA
-917mV    11.31mA    7.645mA    22.57mA
-815mV    8.625mA    5.831mA    17.67mA
-611mV    2.953mA    2.495mA    5.465mA
-560mV    1.702mA    1.758mA    3.215mA
-509mV    833.1uA    1.093mA    1.608mA
-458mV    359uA      552.7uA    679.3uA
-254mV    7.444uA    6.928uA    15.57uA
2.5V      0A         0A         3.059nA
[Ramp]
| variable   typ   min   max
dV/dt_r   0.978/0.271n   0.769/0.402n   1.225/0.148n
dV/dt_f   1.052/0.267n   0.801/0.394n   1.263/0.166n
R_load = 50.000
[Rising Waveform]
R_fixture= 50.000
V_fixture= 0.0
V_fixture_min= 0.0
V_fixture_max= 0.0
|time   V(typ)   V(min)   V(max)
0s        7.849nV    52.48nV    23.59nV
596ps     -189.4uV   2.392uV    -29.45mV
789ps     -945.9uV   2.392uV    1.588V
1.039ns   -43.33mV   -253.4uV   1.927V
1.243ns   867.2mV    -517.2uV   1.978V
1.401ns   1.292V     -3.62mV    2V
1.752ns   1.521V     201.7uV    2.024V
2.231ns   1.586V     1.004V     2.036V
2.88ns    1.616V     1.216V     2.04V
20ns      1.629V     1.281V     2.041V
[Rising Waveform]
R_fixture= 50.000
V_fixture= 2.500
V_fixture_min= 2.380
V_fixture_max= 2.630
|time   V(typ)   V(min)   V(max)
0s        747.2mV    1.044V     524.3mV
555ps     747.1mV    1.045V     540.6mV
746ps     746.9mV    1.044V     2.385V
955ps     823.9mV    1.044V     2.56V
1.138ns   1.909V     1.044V     2.589V
1.326ns   2.388V     1.039V     2.604V
1.529ns   2.444V     1.132V     2.615V
1.918ns   2.472V     2.195V     2.624V
2.377ns   2.487V     2.347V     2.628V
20ns      2.5V       2.38V      2.63V
[Falling Waveform]
R_fixture= 50.000
V_fixture= 2.500
V_fixture_min= 2.380
V_fixture_max= 2.630
|time   V(typ)   V(min)   V(max)
0s        2.5V       2.38V      2.63V
610ps     2.499V     2.38V      2.681V
761ps     2.499V     2.38V      1.347V
865ps     2.5V       2.38V      849.7mV
1.106ns   2.518V     2.379V     606.7mV
1.328ns   1.401V     2.379V     564.8mV
1.763ns   842mV      2.408V     536.5mV
2.345ns   775.3mV    1.356V     527.5mV
3.353ns   752.2mV    1.082V     524.5mV
20ns      747.2mV    1.044V     524.3mV
[Falling Waveform]
R_fixture= 50.000
V_fixture= 0.0
V_fixture_min= 0.0
V_fixture_max= 0.0
|time   V(typ)   V(min)   V(max)
0s        1.629V     1.281V     2.041V
587ps     1.629V     1.281V     2.031V
759ps     1.629V     1.281V     254.4mV
1.022ns   1.6V       1.281V     45.38mV
1.14ns    957.8mV    1.281V     29.02mV
1.366ns   106.4mV    1.282V     14.53mV
1.699ns   27.9mV     1.269V     5.61mV
2.078ns   11.8mV     198.9mV    1.841mV
2.465ns   5.836mV    30.8mV     667.4uV
20ns      -256.3nV   -1.986nV   -79.61nV
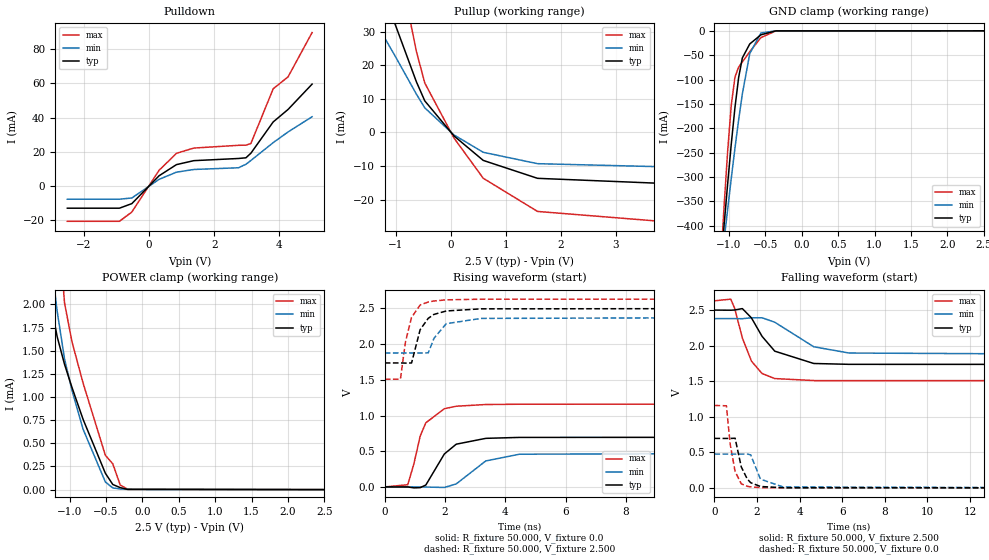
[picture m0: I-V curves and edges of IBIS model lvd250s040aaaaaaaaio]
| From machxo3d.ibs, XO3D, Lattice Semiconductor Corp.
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|   Model lvd250s040aaaaaaaaio
[Model] lvd250s040aaaaaaaaio
Model_type I/O
Polarity   Non-Inverting
Enable   Active-Low
Vinl =  0.700V
Vinh =  1.700V
Vmeas =  1.250V
Cref =  0.0F
Rref =  1.000M
Vref =  0.0V
C_comp   4.200pF   3.800pF   7.500pF
[Temperature Range]   25.000   0.105k   -40.000
[Voltage Range]   2.500V   2.380V   2.630V
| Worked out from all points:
|   slope of the pulldown table from 0 to 0.375 V, typ, clamps not added: 54.4 ohm
|   slope of the pullup table from 0 to 0.375 V, typ, clamps not added: 65.1 ohm
|   GND clamp passes 1 mA (typ) near -0.43 V on its own axis
|   POWER clamp passes 1 mA (typ) near -0.92 V on its own axis
|   rising waveform, R_fixture 50.000, V_fixture 0.0: 20-80 % time 668ps typ, 935ps min, 501ps max; typ from 0 V to 0.696 V
|   rising waveform, R_fixture 50.000, V_fixture 2.500: 20-80 % time 430ps typ, 459ps min, 323ps max; typ from 1.74 V to 2.5 V
|   falling waveform, R_fixture 50.000, V_fixture 2.500: 20-80 % time 1.15ns typ, 1.7ns min, 782ps max; typ from 2.5 V to 1.74 V
|   falling waveform, R_fixture 50.000, V_fixture 0.0: 20-80 % time 429ps typ, 467ps min, 335ps max; typ from 0.696 V to 0 V
[Pulldown]
|Voltage   I(typ)   I(min)   I(max)
-2.5V     -13.08mA   -7.815mA   -20.75mA
-904mV    -13.08mA   -7.815mA   -20.75mA
-524mV    -10.41mA   -7.109mA   -15.34mA
312mV     5.902mA    3.803mA    9.102mA
844mV     12.43mA    8.006mA    19.04mA
1.376V    14.75mA    9.586mA    22.12mA
2.744V    16.02mA    10.59mA    23.73mA
2.972V    16.42mA    12.63mA    23.83mA
3.124V    19.09mA    14.86mA    24.78mA
3.808V    37.42mA    25.31mA    56.82mA
4.264V    44.73mA    31.55mA    63.82mA
5V        59.55mA    40.46mA    89.73mA
[Pullup]
|Voltage   I(typ)   I(min)   I(max)
-2.5V     68.71mA    46.94mA    108.1mA
-2.296V   68.71mA    46.94mA    107.4mA
-1.992V   63.48mA    46.25mA    97.41mA
-1.536V   50.54mA    36.79mA    77.78mA
-1.232V   41.49mA    29.07mA    68.83mA
-1.004V   31.95mA    22.57mA    54.87mA
-624mV    15.09mA    11.42mA    24.13mA
-472mV    9.428mA    7.348mA    14.75mA
60mV      -1.036mA   -745uA     -1.668mA
592mV     -8.336mA   -5.91mA    -13.66mA
1.58V     -13.68mA   -9.308mA   -23.56mA
5V        -15.96mA   -10.7mA    -28.06mA
[GND_clamp]
|Voltage   I(typ)   I(min)   I(max)
-2.5V     -3.262A    -2.545A    -4.485A
-1.123V   -498.5mA   -505.1mA   -498.3mA
-1.072V   -406.1mA   -436mA     -369.4mA
-1.021V   -317.1mA   -368.7mA   -251mA
-970mV    -233.3mA   -303.5mA   -153.4mA
-919mV    -157.7mA   -241.1mA   -95.21mA
-868mV    -95.78mA   -182.7mA   -74.26mA
-817mV    -55.48mA   -129.4mA   -63.96mA
-715mV    -26.89mA   -46.57mA   -42.82mA
-562mV    -8.195mA   -4.484mA   -13.98mA
-358mV    -153.4uA   -68.26uA   -250.2uA
2.5V      0A         0A         0A
[POWER_clamp]
|Voltage   I(typ)   I(min)   I(max)
-2.5V     19.37mA    14.08mA    35.47mA
-1.274V   2.185mA    2.634mA    5.424mA
-1.223V   1.865mA    2.265mA    4.051mA
-1.172V   1.654mA    1.93mA     3.052mA
-1.07V    1.353mA    1.412mA    2.016mA
-968mV    1.104mA    1.071mA    1.597mA
-815mV    758.5uA    651.8uA    1.15mA
-509mV    176.7uA    82.75uA    370.5uA
-407mV    55.24uA    18.01uA    278.8uA
-305mV    21.57uA    6.5uA      49.89uA
-203mV    2.401uA    2.25uA     4.21uA
2.5V      0A         0A         3.059nA
[Ramp]
| variable   typ   min   max
dV/dt_r   0.417/0.667n   0.285/0.915n   0.695/0.501n
dV/dt_f   0.459/1.151n   0.303/1.716n   0.673/0.789n
R_load = 50.000
[Rising Waveform]
R_fixture= 50.000
V_fixture= 0.0
V_fixture_min= 0.0
V_fixture_max= 0.0
|time   V(typ)   V(min)   V(max)
0s        15.97nV    95.33nV    53nV
762ps     -837.3uV   11.27uV    30.45mV
967ps     -13.31mV   -138.5uV   326.6mV
1.175ns   -10.33mV   -403.7uV   713.6mV
1.361ns   26.44mV    -1.647mV   898mV
1.975ns   461.4mV    -8.072mV   1.095V
2.369ns   598.3mV    41.8mV     1.13V
3.349ns   680.1mV    364mV      1.154V
4.464ns   693.3mV    458.2mV    1.158V
20ns      695.7mV    475.2mV    1.159V
[Rising Waveform]
R_fixture= 50.000
V_fixture= 2.500
V_fixture_min= 2.380
V_fixture_max= 2.630
|time   V(typ)   V(min)   V(max)
0s        1.736V     1.876V     1.508V
519ps     1.736V     1.876V     1.51V
684ps     1.734V     1.876V     2.027V
888ps     1.736V     1.876V     2.374V
1.172ns   2.202V     1.875V     2.548V
1.441ns   2.361V     1.878V     2.59V
1.631ns   2.416V     2.081V     2.604V
2.038ns   2.464V     2.286V     2.62V
3.193ns   2.494V     2.36V      2.629V
20ns      2.5V       2.38V      2.63V
[Falling Waveform]
R_fixture= 50.000
V_fixture= 2.500
V_fixture_min= 2.380
V_fixture_max= 2.630
|time   V(typ)   V(min)   V(max)
0s        2.5V       2.38V      2.63V
763ps     2.498V     2.38V      2.654V
948ps     2.501V     2.38V      2.524V
1.31ns    2.521V     2.379V     2.107V
1.736ns   2.39V      2.392V     1.782V
2.234ns   2.131V     2.392V     1.608V
2.832ns   1.922V     2.329V     1.537V
4.663ns   1.749V     1.984V     1.509V
6.324ns   1.737V     1.896V     1.508V
20ns      1.736V     1.876V     1.508V
[Falling Waveform]
R_fixture= 50.000
V_fixture= 0.0
V_fixture_min= 0.0
V_fixture_max= 0.0
|time   V(typ)   V(min)   V(max)
0s        695.7mV    475.1mV    1.159V
559ps     694.9mV    475mV      1.154V
740ps     694.7mV    475.1mV    609.1mV
968ps     698.1mV    474.6mV    229.3mV
1.259ns   293.5mV    474.5mV    56.86mV
1.539ns   124.7mV    475.7mV    21.56mV
1.7ns     72.68mV    463.9mV    13.65mV
2.16ns    19.15mV    122.3mV    3.432mV
3.227ns   2.125mV    12.72mV    216.4uV
20ns      32.23nV    144.7nV    69.21nV
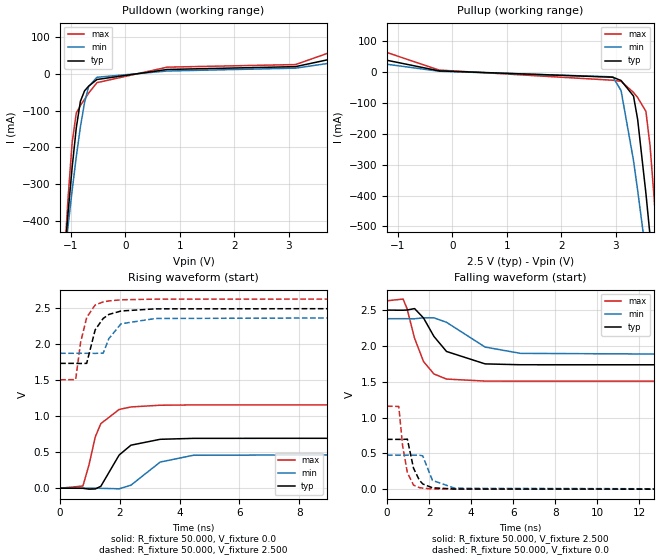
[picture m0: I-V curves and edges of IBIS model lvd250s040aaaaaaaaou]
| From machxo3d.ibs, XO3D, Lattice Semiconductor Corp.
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|   Model lvd250s040aaaaaaaaou
[Model] lvd250s040aaaaaaaaou
Model_type Output
Polarity   Non-Inverting
Enable   Active-High
Vmeas =  1.250V
Cref =  0.0F
Rref =  1.000M
Vref =  0.0V
C_comp   4.200pF   3.800pF   7.500pF
[Temperature Range]   25.000   0.105k   -40.000
[Voltage Range]   2.500V   2.380V   2.630V
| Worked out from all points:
|   slope of the pulldown table from 0 to 0.375 V, typ, clamps not added: 54.4 ohm
|   slope of the pullup table from 0 to 0.375 V, typ, clamps not added: 65.1 ohm
|   rising waveform, R_fixture 50.000, V_fixture 0.0: 20-80 % time 668ps typ, 935ps min, 501ps max; typ from 0 V to 0.696 V
|   rising waveform, R_fixture 50.000, V_fixture 2.500: 20-80 % time 430ps typ, 459ps min, 323ps max; typ from 1.74 V to 2.5 V
|   falling waveform, R_fixture 50.000, V_fixture 2.500: 20-80 % time 1.15ns typ, 1.7ns min, 782ps max; typ from 2.5 V to 1.74 V
|   falling waveform, R_fixture 50.000, V_fixture 0.0: 20-80 % time 429ps typ, 467ps min, 335ps max; typ from 0.696 V to 0 V
[Pulldown]
|Voltage   I(typ)   I(min)   I(max)
-2.5V     -3.262A    -2.545A    -4.486A
-1.132V   -517.4mA   -518.6mA   -526.7mA
-1.056V   -381.2mA   -416.2mA   -341mA
-980mV    -255.2mA   -318mA     -187.6mA
-904mV    -147.7mA   -226.3mA   -107.2mA
-828mV    -74.92mA   -144.7mA   -86.02mA
-752mV    -46.52mA   -78.35mA   -69.69mA
-676mV    -33.59mA   -34.6mA    -52.52mA
-524mV    -15.53mA   -9.507mA   -24.14mA
768mV     11.78mA    7.58mA     18.08mA
3.124V    19.46mA    15.34mA    25.12mA
5V        78.9mA     55.9mA     122.9mA
[Pullup]
|Voltage   I(typ)   I(min)   I(max)
-2.5V     85.48mA    56.73mA    141.3mA
-244mV    4.511mA    3.309mA    7.137mA
2.948V    -16.13mA   -14.92mA   -25.93mA
3.1V      -26.84mA   -59.7mA    -29.58mA
3.328V    -77.1mA    -286.3mA   -65.5mA
3.404V    -152.8mA   -382.7mA   -81.82mA
3.556V    -392.9mA   -588.5mA   -127mA
3.632V    -530.3mA   -695.3mA   -238mA
3.708V    -672.8mA   -803.8mA   -410.9mA
3.784V    -818.6mA   -913.6mA   -606.5mA
3.86V     -966.6mA   -1.024A    -812.2mA
5V        -3.278A    -2.738A    -4.128A
[Ramp]
| variable   typ   min   max
dV/dt_r   0.417/0.667n   0.285/0.915n   0.695/0.501n
dV/dt_f   0.459/1.151n   0.303/1.716n   0.673/0.789n
R_load = 50.000
[Rising Waveform]
R_fixture= 50.000
V_fixture= 0.0
V_fixture_min= 0.0
V_fixture_max= 0.0
|time   V(typ)   V(min)   V(max)
0s        15.97nV    95.33nV    53nV
762ps     -837.3uV   11.27uV    30.45mV
967ps     -13.31mV   -138.5uV   326.6mV
1.175ns   -10.33mV   -403.7uV   713.6mV
1.361ns   26.44mV    -1.647mV   898mV
1.975ns   461.4mV    -8.072mV   1.095V
2.369ns   598.3mV    41.8mV     1.13V
3.349ns   680.1mV    364mV      1.154V
4.464ns   693.3mV    458.2mV    1.158V
20ns      695.7mV    475.2mV    1.159V
[Rising Waveform]
R_fixture= 50.000
V_fixture= 2.500
V_fixture_min= 2.380
V_fixture_max= 2.630
|time   V(typ)   V(min)   V(max)
0s        1.736V     1.876V     1.508V
519ps     1.736V     1.876V     1.51V
684ps     1.734V     1.876V     2.027V
888ps     1.736V     1.876V     2.374V
1.172ns   2.202V     1.875V     2.548V
1.441ns   2.361V     1.878V     2.59V
1.631ns   2.416V     2.081V     2.604V
2.038ns   2.464V     2.286V     2.62V
3.193ns   2.494V     2.36V      2.629V
20ns      2.5V       2.38V      2.63V
[Falling Waveform]
R_fixture= 50.000
V_fixture= 2.500
V_fixture_min= 2.380
V_fixture_max= 2.630
|time   V(typ)   V(min)   V(max)
0s        2.5V       2.38V      2.63V
763ps     2.498V     2.38V      2.654V
948ps     2.501V     2.38V      2.524V
1.31ns    2.521V     2.379V     2.107V
1.736ns   2.39V      2.392V     1.782V
2.234ns   2.131V     2.392V     1.608V
2.832ns   1.922V     2.329V     1.537V
4.665ns   1.749V     1.984V     1.509V
6.344ns   1.737V     1.896V     1.508V
20ns      1.736V     1.876V     1.508V
[Falling Waveform]
R_fixture= 50.000
V_fixture= 0.0
V_fixture_min= 0.0
V_fixture_max= 0.0
|time   V(typ)   V(min)   V(max)
0s        695.7mV    475.1mV    1.159V
559ps     694.9mV    475mV      1.154V
740ps     694.7mV    475.1mV    609.1mV
968ps     698.1mV    474.6mV    229.3mV
1.259ns   293.5mV    474.5mV    56.86mV
1.539ns   124.7mV    475.7mV    21.56mV
1.7ns     72.68mV    463.9mV    13.65mV
2.16ns    19.15mV    122.3mV    3.432mV
3.227ns   2.125mV    12.72mV    216.4uV
20ns      32.24nV    144.7nV    69.21nV
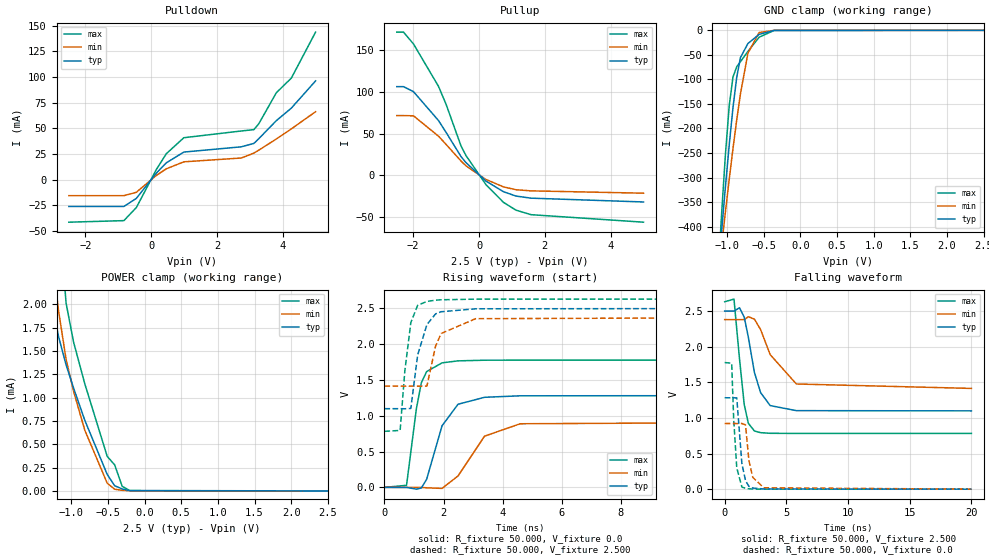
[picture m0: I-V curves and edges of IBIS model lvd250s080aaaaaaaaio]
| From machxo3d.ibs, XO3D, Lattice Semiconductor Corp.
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|   Model lvd250s080aaaaaaaaio
[Model] lvd250s080aaaaaaaaio
Model_type I/O
Polarity   Non-Inverting
Enable   Active-Low
Vinl =  0.700V
Vinh =  1.700V
Vmeas =  1.250V
Cref =  0.0F
Rref =  1.000M
Vref =  0.0V
C_comp   4.200pF   3.800pF   7.500pF
[Temperature Range]   25.000   0.105k   -40.000
[Voltage Range]   2.500V   2.380V   2.630V
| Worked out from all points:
|   slope of the pulldown table from 0 to 0.375 V, typ, clamps not added: 27.2 ohm
|   slope of the pullup table from 0 to 0.375 V, typ, clamps not added: 32.5 ohm
|   GND clamp passes 1 mA (typ) near -0.43 V on its own axis
|   POWER clamp passes 1 mA (typ) near -0.92 V on its own axis
|   rising waveform, R_fixture 50.000, V_fixture 0.0: 20-80 % time 625ps typ, 948ps min, 347ps max; typ from 0 V to 1.28 V
|   rising waveform, R_fixture 50.000, V_fixture 2.500: 20-80 % time 395ps typ, 438ps min, 279ps max; typ from 1.1 V to 2.5 V
|   falling waveform, R_fixture 50.000, V_fixture 2.500: 20-80 % time 1.07ns typ, 1.66ns min, 605ps max; typ from 2.5 V to 1.1 V
|   falling waveform, R_fixture 50.000, V_fixture 0.0: 20-80 % time 426ps typ, 456ps min, 321ps max; typ from 1.28 V to 0 V
[Pulldown]
|Voltage   I(typ)   I(min)   I(max)
-2.5V     -26.15mA   -15.63mA   -41.49mA
-828mV    -26.15mA   -15.63mA   -39.97mA
-448mV    -18.28mA   -12.33mA   -27.2mA
160mV     6.444mA    4.153mA    9.94mA
464mV     16.44mA    10.59mA    25.34mA
996mV     26.9mA     17.37mA    40.9mA
2.744V    32.03mA    21.11mA    47.47mA
3.124V    35.33mA    25.9mA     48.76mA
3.276V    40.02mA    28.82mA    54.65mA
3.808V    57.58mA    39.68mA    84.8mA
4.264V    69.78mA    49.51mA    99.05mA
5V        96.3mA     66.26mA    143.9mA
[Pullup]
|Voltage   I(typ)   I(min)   I(max)
-2.5V     106.1mA    71.5mA     171.4mA
-2.296V   106.1mA    71.5mA     171.4mA
-1.992V   100.1mA    71.18mA    157.2mA
-1.232V   65.55mA    46.85mA    106.5mA
-1.004V   51.53mA    37.08mA    85.28mA
-548mV    22.51mA    17.15mA    35.23mA
-396mV    15.14mA    11.28mA    23.6mA
212mV     -6.926mA   -4.965mA   -11.2mA
744mV     -19.64mA   -13.85mA   -32.38mA
1.124V    -24.85mA   -17.24mA   -41.72mA
1.58V     -27.35mA   -18.62mA   -47.12mA
5V        -31.91mA   -21.4mA    -56.11mA
[GND_clamp]
|Voltage   I(typ)   I(min)   I(max)
-2.5V     -3.262A    -2.545A    -4.485A
-1.123V   -498.5mA   -505.1mA   -498.3mA
-1.072V   -406.1mA   -436mA     -369.4mA
-1.021V   -317.1mA   -368.7mA   -251mA
-970mV    -233.3mA   -303.5mA   -153.4mA
-919mV    -157.7mA   -241.1mA   -95.21mA
-868mV    -95.78mA   -182.7mA   -74.26mA
-817mV    -55.48mA   -129.4mA   -63.96mA
-715mV    -26.89mA   -46.57mA   -42.82mA
-562mV    -8.195mA   -4.484mA   -13.98mA
-358mV    -153.4uA   -68.26uA   -250.2uA
2.5V      0A         0A         0A
[POWER_clamp]
|Voltage   I(typ)   I(min)   I(max)
-2.5V     19.37mA    14.08mA    35.47mA
-1.274V   2.185mA    2.634mA    5.424mA
-1.223V   1.865mA    2.265mA    4.051mA
-1.172V   1.654mA    1.93mA     3.052mA
-1.07V    1.353mA    1.412mA    2.016mA
-968mV    1.104mA    1.071mA    1.597mA
-815mV    758.5uA    651.8uA    1.15mA
-509mV    176.7uA    82.75uA    370.5uA
-407mV    55.24uA    18.01uA    278.8uA
-305mV    21.57uA    6.5uA      49.89uA
-203mV    2.401uA    2.25uA     4.21uA
2.5V      0A         0A         3.059nA
[Ramp]
| variable   typ   min   max
dV/dt_r   0.770/0.625n   0.553/0.933n   1.066/0.346n
dV/dt_f   0.841/1.063n   0.579/1.667n   1.108/0.604n
R_load = 50.000
[Rising Waveform]
R_fixture= 50.000
V_fixture= 0.0
V_fixture_min= 0.0
V_fixture_max= 0.0
|time   V(typ)   V(min)   V(max)
0s        10.52nV    67.42nV    32.65nV
748ps     -747.5uV   5.474uV    28.88mV
1.083ns   -24.92mV   -332.1uV   1.104V
1.249ns   -8.166mV   -471.3uV   1.461V
1.428ns   112.8mV    -6.242mV   1.617V
1.949ns   859.9mV    -14.22mV   1.739V
2.491ns   1.161V     159.6mV    1.767V
3.387ns   1.258V     715.1mV    1.776V
4.593ns   1.279V     888.5mV    1.777V
20ns      1.283V     921.3mV    1.777V
[Rising Waveform]
R_fixture= 50.000
V_fixture= 2.500
V_fixture_min= 2.380
V_fixture_max= 2.630
|time   V(typ)   V(min)   V(max)
0s        1.099V     1.414V     783mV
531ps     1.099V     1.414V     795mV
689ps     1.098V     1.414V     1.62V
893ps     1.103V     1.414V     2.302V
1.124ns   1.848V     1.413V     2.543V
1.437ns   2.273V     1.414V     2.597V
1.731ns   2.423V     1.974V     2.614V
1.918ns   2.453V     2.149V     2.62V
3.087ns   2.494V     2.356V     2.629V
20ns      2.5V       2.38V      2.63V
[Falling Waveform]
R_fixture= 50.000
V_fixture= 2.500
V_fixture_min= 2.380
V_fixture_max= 2.630
|time   V(typ)   V(min)   V(max)
0s        2.5V       2.38V      2.63V
753ps     2.499V     2.38V      2.668V
1.197ns   2.546V     2.379V     1.835V
1.584ns   2.415V     2.379V     1.187V
1.918ns   2.131V     2.42V      924.1mV
2.409ns   1.638V     2.386V     816.9mV
2.913ns   1.354V     2.239V     792.9mV
3.687ns   1.173V     1.888V     784.1mV
5.81ns    1.102V     1.476V     782.5mV
20ns      1.099V     1.414V     782.4mV
[Falling Waveform]
R_fixture= 50.000
V_fixture= 0.0
V_fixture_min= 0.0
V_fixture_max= 0.0
|time   V(typ)   V(min)   V(max)
0s        1.283V     921.3mV    1.777V
566ps     1.282V     921.2mV    1.768V
731ps     1.282V     921.3mV    975.3mV
978ps     1.281V     920.9mV    300.4mV
1.394ns   358.8mV    922mV      29.33mV
1.689ns   119.2mV    902.8mV    12.07mV
1.962ns   39.63mV    402.1mV    5.168mV
2.278ns   16.37mV    165.5mV    1.953mV
3.168ns   2.66mV     19.45mV    201.1uV
20ns      28.91nV    127nV      85.58nV
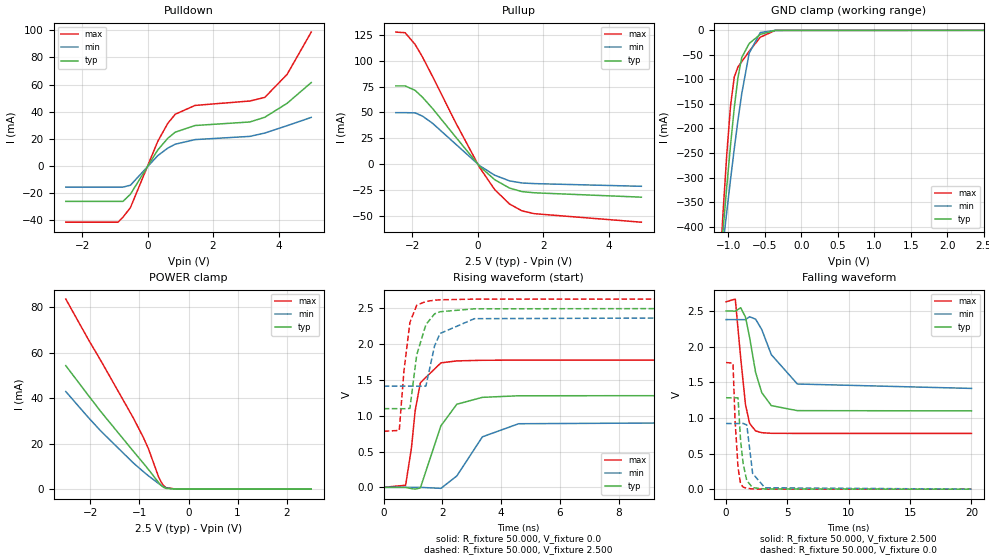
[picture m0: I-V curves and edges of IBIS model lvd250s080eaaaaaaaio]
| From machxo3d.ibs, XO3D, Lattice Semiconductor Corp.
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|   Model lvd250s080eaaaaaaaio
[Model] lvd250s080eaaaaaaaio
Model_type I/O
Polarity   Non-Inverting
Enable   Active-Low
Vinl =  0.700V
Vinh =  1.700V
Vmeas =  1.250V
Cref =  0.0F
Rref =  1.000M
Vref =  0.0V
C_comp   4.200pF   3.800pF   7.500pF
[Temperature Range]   25.000   0.105k   -40.000
[Voltage Range]   2.500V   2.380V   2.630V
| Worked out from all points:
|   slope of the pulldown table from 0 to 0.375 V, typ, clamps not added: 27.2 ohm
|   slope of the pullup table from 0 to 0.375 V, typ, clamps not added: 32.5 ohm
|   GND clamp passes 1 mA (typ) near -0.43 V on its own axis
|   POWER clamp passes 1 mA (typ) near -0.52 V on its own axis
|   rising waveform, R_fixture 50.000, V_fixture 0.0: 20-80 % time 625ps typ, 941ps min, 346ps max; typ from 0 V to 1.28 V
|   rising waveform, R_fixture 50.000, V_fixture 2.500: 20-80 % time 395ps typ, 438ps min, 279ps max; typ from 1.1 V to 2.5 V
|   falling waveform, R_fixture 50.000, V_fixture 2.500: 20-80 % time 1.07ns typ, 1.66ns min, 605ps max; typ from 2.5 V to 1.1 V
|   falling waveform, R_fixture 50.000, V_fixture 0.0: 20-80 % time 426ps typ, 454ps min, 321ps max; typ from 1.28 V to 0 V
[Pulldown]
|Voltage   I(typ)   I(min)   I(max)
-2.5V     -26.15mA   -15.63mA   -41.49mA
-904mV    -26.15mA   -15.63mA   -41.49mA
-752mV    -26.15mA   -15.63mA   -37.84mA
-524mV    -20.82mA   -14.22mA   -30.68mA
312mV     11.8mA     7.606mA    18.2mA
616mV     20.36mA    13.11mA    31.35mA
844mV     24.87mA    16.01mA    38.07mA
1.452V    29.78mA    19.39mA    44.59mA
3.124V    32.39mA    21.76mA    47.83mA
3.58V     35.84mA    24.22mA    50.47mA
4.264V    46.16mA    29.66mA    67.51mA
5V        61.43mA    35.76mA    98.64mA
[Pullup]
|Voltage   I(typ)   I(min)   I(max)
-2.5V     75.68mA    49.8mA     127.7mA
-2.22V    75.68mA    49.8mA     127.1mA
-1.916V   71.4mA     49.61mA    115.9mA
-1.688V   64.69mA    46.47mA    103.6mA
-1.384V   53.94mA    39.6mA     84.98mA
-700mV    27.27mA    20.14mA    41.68mA
60mV      -2.071mA   -1.49mA    -3.336mA
516mV     -14.99mA   -10.65mA   -24.49mA
972mV     -23.14mA   -16.17mA   -38.54mA
1.352V    -26.53mA   -18.19mA   -45.15mA
1.732V    -27.69mA   -18.81mA   -47.89mA
5V        -31.91mA   -21.4mA    -56.11mA
[GND_clamp]
|Voltage   I(typ)   I(min)   I(max)
-2.5V     -3.262A    -2.545A    -4.485A
-1.123V   -498.5mA   -505.1mA   -498.3mA
-1.072V   -406.1mA   -436mA     -369.4mA
-1.021V   -317.1mA   -368.7mA   -251mA
-970mV    -233.3mA   -303.5mA   -153.4mA
-919mV    -157.7mA   -241.1mA   -95.21mA
-868mV    -95.78mA   -182.7mA   -74.26mA
-817mV    -55.48mA   -129.4mA   -63.96mA
-715mV    -26.89mA   -46.57mA   -42.82mA
-562mV    -8.195mA   -4.484mA   -13.98mA
-358mV    -153.4uA   -68.26uA   -250.2uA
2.5V      0A         0A         0A
[POWER_clamp]
|Voltage   I(typ)   I(min)   I(max)
-2.5V     54.23mA    42.85mA    83.47mA
-2.039V   41.12mA    31.42mA    65.66mA
-1.784V   33.99mA    25.46mA    56.34mA
-1.121V   16.56mA    11.45mA    31.14mA
-917mV    11.31mA    7.645mA    22.57mA
-815mV    8.625mA    5.831mA    17.67mA
-611mV    2.953mA    2.495mA    5.465mA
-560mV    1.702mA    1.758mA    3.215mA
-509mV    833.1uA    1.093mA    1.608mA
-458mV    359uA      552.7uA    679.3uA
-254mV    7.444uA    6.928uA    15.57uA
2.5V      0A         0A         3.059nA
[Ramp]
| variable   typ   min   max
dV/dt_r   0.770/0.625n   0.553/0.933n   1.066/0.346n
dV/dt_f   0.841/1.063n   0.579/1.667n   1.108/0.604n
R_load = 50.000
[Rising Waveform]
R_fixture= 50.000
V_fixture= 0.0
V_fixture_min= 0.0
V_fixture_max= 0.0
|time   V(typ)   V(min)   V(max)
0s        10.52nV    67.42nV    32.64nV
748ps     -747.5uV   5.475uV    29.08mV
946ps     -17.54mV   -18.49uV   551.5mV
1.071ns   -25.59mV   -356.2uV   1.067V
1.249ns   -8.166mV   -471.3uV   1.461V
1.949ns   859.9mV    -14.22mV   1.739V
2.491ns   1.161V     159.6mV    1.766V
3.36ns    1.257V     705.7mV    1.775V
4.593ns   1.279V     888.5mV    1.777V
20ns      1.283V     921.3mV    1.777V
[Rising Waveform]
R_fixture= 50.000
V_fixture= 2.500
V_fixture_min= 2.380
V_fixture_max= 2.630
|time   V(typ)   V(min)   V(max)
0s        1.099V     1.414V     783mV
531ps     1.099V     1.414V     795mV
689ps     1.098V     1.414V     1.62V
893ps     1.103V     1.414V     2.302V
1.124ns   1.848V     1.413V     2.543V
1.437ns   2.273V     1.414V     2.597V
1.731ns   2.423V     1.974V     2.614V
1.918ns   2.453V     2.149V     2.62V
3.087ns   2.494V     2.356V     2.629V
20ns      2.5V       2.38V      2.63V
[Falling Waveform]
R_fixture= 50.000
V_fixture= 2.500
V_fixture_min= 2.380
V_fixture_max= 2.630
|time   V(typ)   V(min)   V(max)
0s        2.5V       2.38V      2.63V
753ps     2.499V     2.38V      2.668V
1.197ns   2.546V     2.379V     1.835V
1.584ns   2.415V     2.379V     1.187V
1.918ns   2.131V     2.42V      924.1mV
2.409ns   1.638V     2.386V     816.9mV
2.913ns   1.354V     2.239V     792.9mV
3.687ns   1.173V     1.888V     784.1mV
5.81ns    1.102V     1.476V     782.5mV
20ns      1.099V     1.414V     782.4mV
[Falling Waveform]
R_fixture= 50.000
V_fixture= 0.0
V_fixture_min= 0.0
V_fixture_max= 0.0
|time   V(typ)   V(min)   V(max)
0s        1.283V     921.3mV    1.777V
566ps     1.282V     921.2mV    1.768V
731ps     1.282V     921.3mV    975.3mV
978ps     1.281V     920.9mV    300.4mV
1.186ns   678mV      921mV      72.54mV
1.394ns   358.8mV    922mV      29.33mV
1.69ns    119.2mV    902mV      12.07mV
2.168ns   21.3mV     219.1mV    2.976mV
3.168ns   2.66mV     19.45mV    201.1uV
20ns      28.91nV    127nV      85.58nV
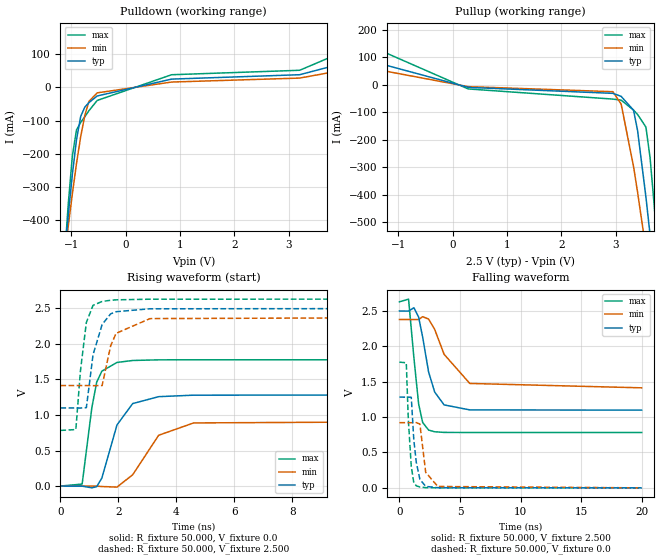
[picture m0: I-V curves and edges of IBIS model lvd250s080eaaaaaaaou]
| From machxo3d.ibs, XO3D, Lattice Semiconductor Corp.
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|   Model lvd250s080eaaaaaaaou
[Model] lvd250s080eaaaaaaaou
Model_type Output
Polarity   Non-Inverting
Enable   Active-High
Vmeas =  1.250V
Cref =  0.0F
Rref =  1.000M
Vref =  0.0V
C_comp   4.200pF   3.800pF   7.500pF
[Temperature Range]   25.000   0.105k   -40.000
[Voltage Range]   2.500V   2.380V   2.630V
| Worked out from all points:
|   slope of the pulldown table from 0 to 0.375 V, typ, clamps not added: 27.2 ohm
|   slope of the pullup table from 0 to 0.375 V, typ, clamps not added: 32.5 ohm
|   rising waveform, R_fixture 50.000, V_fixture 0.0: 20-80 % time 625ps typ, 948ps min, 347ps max; typ from 0 V to 1.28 V
|   rising waveform, R_fixture 50.000, V_fixture 2.500: 20-80 % time 395ps typ, 438ps min, 279ps max; typ from 1.1 V to 2.5 V
|   falling waveform, R_fixture 50.000, V_fixture 2.500: 20-80 % time 1.07ns typ, 1.66ns min, 605ps max; typ from 2.5 V to 1.1 V
|   falling waveform, R_fixture 50.000, V_fixture 0.0: 20-80 % time 426ps typ, 454ps min, 321ps max; typ from 1.28 V to 0 V
[Pulldown]
|Voltage   I(typ)   I(min)   I(max)
-2.5V     -3.262A    -2.546A    -4.486A
-1.132V   -519.7mA   -519.8mA   -531.8mA
-1.056V   -384.7mA   -417.6mA   -351.2mA
-980mV    -261.1mA   -319.9mA   -205.2mA
-904mV    -157.6mA   -229mA     -128mA
-828mV    -87.78mA   -148.9mA   -106mA
-752mV    -59.6mA    -84.62mA   -88.61mA
-676mV    -45.95mA   -42.35mA   -70.41mA
-524mV    -25.94mA   -16.62mA   -39.48mA
844mV     24.87mA    16.01mA    38.07mA
3.2V      38.14mA    27.99mA    51.53mA
5V        115.7mA    81.7mA     177.1mA
[Pullup]
|Voltage   I(typ)   I(min)   I(max)
-2.5V     122.7mA    81.15mA    204.4mA
-2.068V   116.6mA    81.15mA    189.3mA
288mV     -9.146mA   -6.543mA   -14.83mA
2.948V    -30.91mA   -24.9mA    -51.76mA
3.1V      -41.72mA   -69.76mA   -55.59mA
3.328V    -92.14mA   -296.5mA   -91.8mA
3.404V    -167.9mA   -392.9mA   -108.2mA
3.556V    -408.1mA   -598.7mA   -153.6mA
3.632V    -545.5mA   -705.6mA   -264.6mA
3.708V    -688.1mA   -814.1mA   -437.6mA
3.784V    -833.9mA   -923.9mA   -633.3mA
5V        -3.294A    -2.749A    -4.156A
[Ramp]
| variable   typ   min   max
dV/dt_r   0.770/0.625n   0.553/0.933n   1.066/0.346n
dV/dt_f   0.841/1.063n   0.579/1.667n   1.108/0.604n
R_load = 50.000
[Rising Waveform]
R_fixture= 50.000
V_fixture= 0.0
V_fixture_min= 0.0
V_fixture_max= 0.0
|time   V(typ)   V(min)   V(max)
0s        10.52nV    67.42nV    32.65nV
748ps     -747.5uV   5.476uV    28.88mV
1.083ns   -24.92mV   -332.1uV   1.104V
1.249ns   -8.166mV   -471.3uV   1.461V
1.428ns   112.8mV    -6.242mV   1.617V
1.949ns   859.9mV    -14.22mV   1.739V
2.491ns   1.161V     159.6mV    1.767V
3.387ns   1.258V     715.1mV    1.776V
4.593ns   1.279V     888.5mV    1.777V
20ns      1.283V     921.3mV    1.777V
[Rising Waveform]
R_fixture= 50.000
V_fixture= 2.500
V_fixture_min= 2.380
V_fixture_max= 2.630
|time   V(typ)   V(min)   V(max)
0s        1.099V     1.414V     783mV
531ps     1.099V     1.414V     795mV
689ps     1.098V     1.414V     1.62V
893ps     1.103V     1.414V     2.302V
1.124ns   1.848V     1.413V     2.543V
1.437ns   2.273V     1.414V     2.597V
1.731ns   2.423V     1.974V     2.614V
1.918ns   2.453V     2.149V     2.62V
3.087ns   2.494V     2.356V     2.629V
20ns      2.5V       2.38V      2.63V
[Falling Waveform]
R_fixture= 50.000
V_fixture= 2.500
V_fixture_min= 2.380
V_fixture_max= 2.630
|time   V(typ)   V(min)   V(max)
0s        2.5V       2.38V      2.63V
753ps     2.499V     2.38V      2.668V
1.197ns   2.546V     2.379V     1.835V
1.584ns   2.415V     2.379V     1.187V
1.918ns   2.131V     2.42V      924.1mV
2.409ns   1.638V     2.386V     816.9mV
2.913ns   1.354V     2.239V     792.9mV
3.687ns   1.173V     1.888V     784.1mV
5.81ns    1.102V     1.476V     782.5mV
20ns      1.099V     1.414V     782.4mV
[Falling Waveform]
R_fixture= 50.000
V_fixture= 0.0
V_fixture_min= 0.0
V_fixture_max= 0.0
|time   V(typ)   V(min)   V(max)
0s        1.283V     921.3mV    1.777V
566ps     1.282V     921.2mV    1.768V
731ps     1.282V     921.3mV    975.3mV
978ps     1.281V     920.9mV    300.4mV
1.186ns   678mV      921mV      72.54mV
1.394ns   358.8mV    922mV      29.33mV
1.69ns    119.2mV    902mV      12.07mV
2.168ns   21.3mV     219.1mV    2.976mV
3.168ns   2.66mV     19.45mV    201.1uV
20ns      28.91nV    127nV      85.58nV
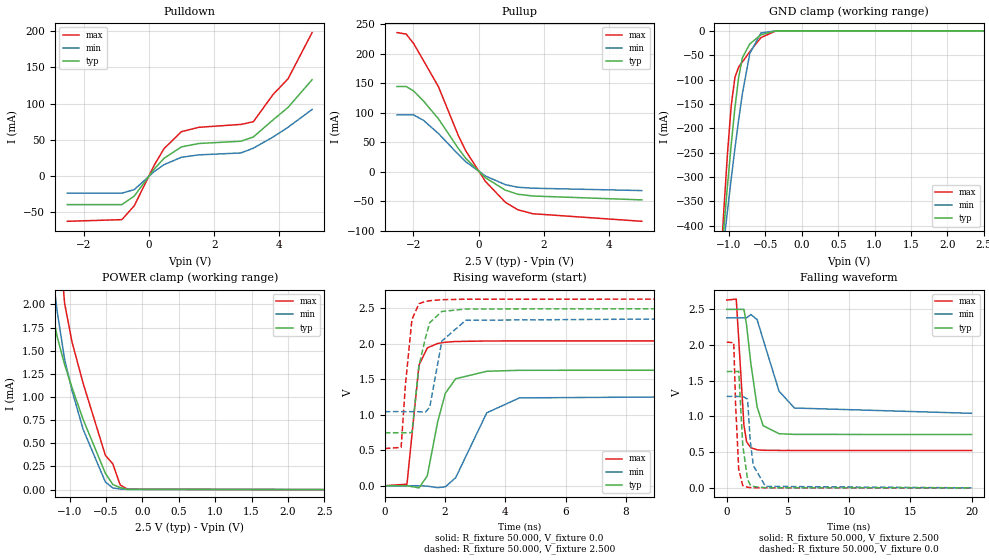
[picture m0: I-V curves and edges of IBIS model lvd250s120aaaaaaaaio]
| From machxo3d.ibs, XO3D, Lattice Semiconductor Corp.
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|   Model lvd250s120aaaaaaaaio
[Model] lvd250s120aaaaaaaaio
Model_type I/O
Polarity   Non-Inverting
Enable   Active-Low
Vinl =  0.700V
Vinh =  1.700V
Vmeas =  1.250V
Cref =  0.0F
Rref =  1.000M
Vref =  0.0V
C_comp   4.200pF   3.800pF   7.500pF
[Temperature Range]   25.000   0.105k   -40.000
[Voltage Range]   2.500V   2.380V   2.630V
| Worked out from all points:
|   slope of the pulldown table from 0 to 0.375 V, typ, clamps not added: 18.1 ohm
|   slope of the pullup table from 0 to 0.375 V, typ, clamps not added: 21.7 ohm
|   GND clamp passes 1 mA (typ) near -0.43 V on its own axis
|   POWER clamp passes 1 mA (typ) near -0.92 V on its own axis
|   rising waveform, R_fixture 50.000, V_fixture 0.0: 20-80 % time 504ps typ, 872ps min, 258ps max; typ from 0 V to 1.63 V
|   rising waveform, R_fixture 50.000, V_fixture 2.500: 20-80 % time 386ps typ, 429ps min, 255ps max; typ from 0.747 V to 2.5 V
|   falling waveform, R_fixture 50.000, V_fixture 2.500: 20-80 % time 818ps typ, 1.5ns min, 419ps max; typ from 2.5 V to 0.747 V
|   falling waveform, R_fixture 50.000, V_fixture 0.0: 20-80 % time 428ps typ, 467ps min, 289ps max; typ from 1.63 V to 0 V
[Pulldown]
|Voltage   I(typ)   I(min)   I(max)
-2.5V     -39.23mA   -23.44mA   -62.24mA
-828mV    -39.23mA   -23.44mA   -59.96mA
-448mV    -27.42mA   -18.49mA   -40.8mA
160mV     9.666mA    6.229mA    14.91mA
464mV     24.66mA    15.88mA    38.02mA
996mV     40.36mA    26.05mA    61.35mA
1.528V    45.04mA    29.35mA    67.36mA
2.82V     48.16mA    32.01mA    71.35mA
3.2V      54.04mA    38.6mA     75.05mA
3.808V    77.75mA    54.05mA    112.8mA
4.264V    94.83mA    67.48mA    134.3mA
5V        133mA      91.99mA    198mA
[Pullup]
|Voltage   I(typ)   I(min)   I(max)
-2.5V     144.2mA    96.17mA    235.7mA
-2.22V    144.2mA    96.17mA    233.2mA
-1.992V   136.8mA    96.17mA    217.2mA
-1.688V   119.7mA    86.91mA    188.1mA
-1.232V   89.61mA    64.63mA    144.1mA
-624mV    39.38mA    29.34mA    61.43mA
-396mV    22.67mA    16.85mA    35.4mA
212mV     -10.39mA   -7.447mA   -16.81mA
820mV     -31.4mA    -22.08mA   -51.93mA
1.2V      -38.29mA   -26.46mA   -64.56mA
1.656V    -41.29mA   -28.07mA   -71.31mA
5V        -47.87mA   -32.1mA    -84.17mA
[GND_clamp]
|Voltage   I(typ)   I(min)   I(max)
-2.5V     -3.262A    -2.545A    -4.485A
-1.123V   -498.5mA   -505.1mA   -498.3mA
-1.072V   -406.1mA   -436mA     -369.4mA
-1.021V   -317.1mA   -368.7mA   -251mA
-970mV    -233.3mA   -303.5mA   -153.4mA
-919mV    -157.7mA   -241.1mA   -95.21mA
-868mV    -95.78mA   -182.7mA   -74.26mA
-817mV    -55.48mA   -129.4mA   -63.96mA
-715mV    -26.89mA   -46.57mA   -42.82mA
-562mV    -8.195mA   -4.484mA   -13.98mA
-358mV    -153.4uA   -68.26uA   -250.2uA
2.5V      0A         0A         0A
[POWER_clamp]
|Voltage   I(typ)   I(min)   I(max)
-2.5V     19.37mA    14.08mA    35.47mA
-1.274V   2.185mA    2.634mA    5.424mA
-1.223V   1.865mA    2.265mA    4.051mA
-1.172V   1.654mA    1.93mA     3.052mA
-1.07V    1.353mA    1.412mA    2.016mA
-968mV    1.104mA    1.071mA    1.597mA
-815mV    758.5uA    651.8uA    1.15mA
-509mV    176.7uA    82.75uA    370.5uA
-407mV    55.24uA    18.01uA    278.8uA
-305mV    21.57uA    6.5uA      49.89uA
-203mV    2.401uA    2.25uA     4.21uA
2.5V      0A         0A         3.059nA
[Ramp]
| variable   typ   min   max
dV/dt_r   0.978/0.506n   0.769/0.879n   1.225/0.256n
dV/dt_f   1.052/0.820n   0.801/1.483n   1.263/0.420n
R_load = 50.000
[Rising Waveform]
R_fixture= 50.000
V_fixture= 0.0
V_fixture_min= 0.0
V_fixture_max= 0.0
|time   V(typ)   V(min)   V(max)
0s        7.849nV    52.32nV    23.6nV
736ps     -521.9uV   1.787uV    21.47mV
1.137ns   -29.85mV   -309.6uV   1.701V
1.411ns   139.6mV    -5.406mV   1.943V
1.754ns   897.2mV    -26.95mV   2.005V
2.01ns    1.303V     -15.69mV   2.023V
2.354ns   1.508V     114.1mV    2.033V
3.385ns   1.613V     1.028V     2.04V
4.469ns   1.627V     1.238V     2.041V
20ns      1.629V     1.281V     2.041V
[Rising Waveform]
R_fixture= 50.000
V_fixture= 2.500
V_fixture_min= 2.380
V_fixture_max= 2.630
|time   V(typ)   V(min)   V(max)
0s        747.2mV    1.044V     524.3mV
542ps     747.2mV    1.045V     540.1mV
686ps     746.2mV    1.044V     1.426V
900ps     750.1mV    1.044V     2.341V
1.133ns   1.686V     1.044V     2.565V
1.35ns    2.083V     1.037V     2.598V
1.493ns   2.299V     1.108V     2.608V
1.894ns   2.456V     2.039V     2.622V
2.688ns   2.491V     2.332V     2.629V
20ns      2.5V       2.38V      2.63V
[Falling Waveform]
R_fixture= 50.000
V_fixture= 2.500
V_fixture_min= 2.380
V_fixture_max= 2.630
|time   V(typ)   V(min)   V(max)
0s        2.5V       2.38V      2.63V
779ps     2.499V     2.38V      2.643V
1.404ns   2.5V       2.381V     880.1mV
1.622ns   2.281V     2.381V     646mV
1.974ns   1.738V     2.428V     561mV
2.485ns   1.133V     2.355V     532.7mV
2.973ns   871.1mV    2.078V     526.5mV
4.275ns   758.1mV    1.354V     524.4mV
5.533ns   748.7mV    1.118V     524.3mV
20ns      747.1mV    1.044V     524.3mV
[Falling Waveform]
R_fixture= 50.000
V_fixture= 0.0
V_fixture_min= 0.0
V_fixture_max= 0.0
|time   V(typ)   V(min)   V(max)
0s        1.629V     1.281V     2.041V
574ps     1.629V     1.281V     2.032V
728ps     1.629V     1.281V     1.157V
980ps     1.631V     1.281V     259mV
1.312ns   591.1mV    1.282V     29.84mV
1.705ns   117.8mV    1.242V     8.573mV
1.912ns   43.16mV    673.2mV    4.592mV
2.173ns   18.74mV    311.6mV    2.19mV
3.169ns   2.508mV    21.03mV    172uV
20ns      27.28nV    114nV      82.28nV
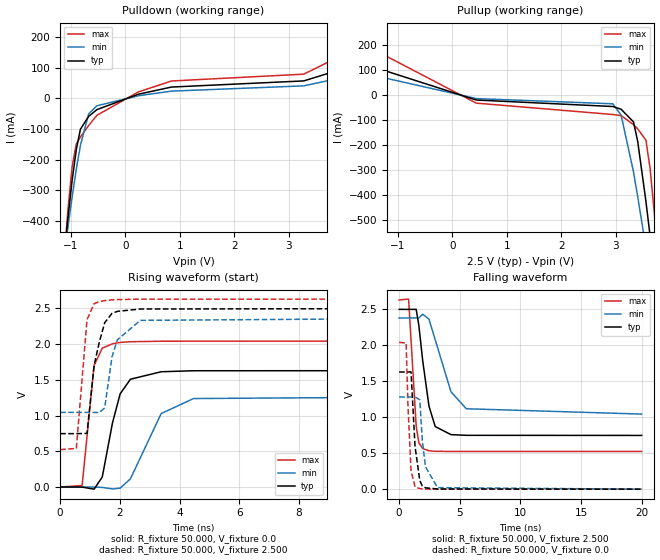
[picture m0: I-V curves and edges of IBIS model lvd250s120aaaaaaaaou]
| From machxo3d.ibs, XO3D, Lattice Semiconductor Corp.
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|   Model lvd250s120aaaaaaaaou
[Model] lvd250s120aaaaaaaaou
Model_type Output
Polarity   Non-Inverting
Enable   Active-High
Vmeas =  1.250V
Cref =  0.0F
Rref =  1.000M
Vref =  0.0V
C_comp   4.200pF   3.800pF   7.500pF
[Temperature Range]   25.000   0.105k   -40.000
[Voltage Range]   2.500V   2.380V   2.630V
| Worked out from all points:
|   slope of the pulldown table from 0 to 0.375 V, typ, clamps not added: 18.1 ohm
|   slope of the pullup table from 0 to 0.375 V, typ, clamps not added: 21.7 ohm
|   rising waveform, R_fixture 50.000, V_fixture 0.0: 20-80 % time 504ps typ, 872ps min, 258ps max; typ from 0 V to 1.63 V
|   rising waveform, R_fixture 50.000, V_fixture 2.500: 20-80 % time 386ps typ, 432ps min, 255ps max; typ from 0.747 V to 2.5 V
|   falling waveform, R_fixture 50.000, V_fixture 2.500: 20-80 % time 818ps typ, 1.5ns min, 419ps max; typ from 2.5 V to 0.747 V
|   falling waveform, R_fixture 50.000, V_fixture 0.0: 20-80 % time 428ps typ, 467ps min, 289ps max; typ from 1.63 V to 0 V
[Pulldown]
|Voltage   I(typ)   I(min)   I(max)
-2.5V     -3.263A    -2.546A    -4.486A
-1.132V   -522.1mA   -521mA     -536.8mA
-1.056V   -388.2mA   -419.1mA   -361.5mA
-980mV    -267.1mA   -321.9mA   -222.8mA
-904mV    -167.6mA   -231.8mA   -148.7mA
-828mV    -100.6mA   -153.1mA   -126mA
-676mV    -58.31mA   -50.11mA   -88.3mA
-524mV    -36.34mA   -23.73mA   -54.82mA
236mV     13.82mA    8.909mA    21.32mA
844mV     37.3mA     24.02mA    57.11mA
3.276V    57.4mA     41.23mA    79.45mA
5V        152.4mA    107.4mA    231.2mA
[Pullup]
|Voltage   I(typ)   I(min)   I(max)
-2.5V     160.2mA    105.8mA    268.1mA
-1.992V   149.7mA    105.1mA    243.3mA
440mV     -19.77mA   -14.08mA   -32.21mA
2.948V    -45.68mA   -34.89mA   -77.59mA
3.1V      -56.59mA   -79.82mA   -81.6mA
3.328V    -107.2mA   -306.6mA   -118.1mA
3.404V    -183mA     -403.1mA   -134.6mA
3.556V    -423.3mA   -609mA     -180.1mA
3.632V    -560.8mA   -715.9mA   -291.3mA
3.708V    -703.4mA   -824.4mA   -464.4mA
3.784V    -849.3mA   -934.3mA   -660.2mA
5V        -3.31A     -2.76A     -4.184A
[Ramp]
| variable   typ   min   max
dV/dt_r   0.978/0.506n   0.769/0.879n   1.225/0.256n
dV/dt_f   1.052/0.820n   0.801/1.483n   1.263/0.420n
R_load = 50.000
[Rising Waveform]
R_fixture= 50.000
V_fixture= 0.0
V_fixture_min= 0.0
V_fixture_max= 0.0
|time   V(typ)   V(min)   V(max)
0s        7.849nV    52.32nV    23.6nV
736ps     -521.9uV   1.789uV    21.47mV
1.137ns   -29.85mV   -309.7uV   1.701V
1.411ns   139.6mV    -5.406mV   1.943V
1.754ns   897.2mV    -26.95mV   2.005V
2.01ns    1.303V     -15.69mV   2.023V
2.354ns   1.508V     114.1mV    2.033V
3.385ns   1.613V     1.028V     2.04V
4.469ns   1.627V     1.238V     2.041V
20ns      1.629V     1.281V     2.041V
[Rising Waveform]
R_fixture= 50.000
V_fixture= 2.500
V_fixture_min= 2.380
V_fixture_max= 2.630
|time   V(typ)   V(min)   V(max)
0s        747.2mV    1.044V     524.3mV
542ps     747.2mV    1.045V     540.1mV
900ps     750.1mV    1.044V     2.341V
1.139ns   1.704V     1.044V     2.566V
1.313ns   2.029V     1.042V     2.594V
1.493ns   2.299V     1.108V     2.608V
1.738ns   2.43V      1.823V     2.619V
1.918ns   2.458V     2.06V      2.623V
2.688ns   2.491V     2.332V     2.629V
20ns      2.5V       2.38V      2.63V
[Falling Waveform]
R_fixture= 50.000
V_fixture= 2.500
V_fixture_min= 2.380
V_fixture_max= 2.630
|time   V(typ)   V(min)   V(max)
0s        2.5V       2.38V      2.63V
779ps     2.499V     2.38V      2.643V
1.404ns   2.5V       2.381V     880.1mV
1.622ns   2.281V     2.381V     646mV
1.942ns   1.787V     2.432V     565mV
2.461ns   1.154V     2.363V     533.3mV
2.973ns   871.1mV    2.078V     526.5mV
4.275ns   758.1mV    1.354V     524.4mV
5.533ns   748.7mV    1.118V     524.3mV
20ns      747.1mV    1.044V     524.3mV
[Falling Waveform]
R_fixture= 50.000
V_fixture= 0.0
V_fixture_min= 0.0
V_fixture_max= 0.0
|time   V(typ)   V(min)   V(max)
0s        1.629V     1.281V     2.041V
574ps     1.629V     1.281V     2.032V
728ps     1.629V     1.281V     1.157V
980ps     1.631V     1.281V     259mV
1.312ns   591.1mV    1.282V     29.84mV
1.705ns   117.8mV    1.242V     8.573mV
1.912ns   43.16mV    673.2mV    4.592mV
2.173ns   18.74mV    311.6mV    2.19mV
3.169ns   2.508mV    21.03mV    172uV
20ns      27.28nV    114nV      82.28nV
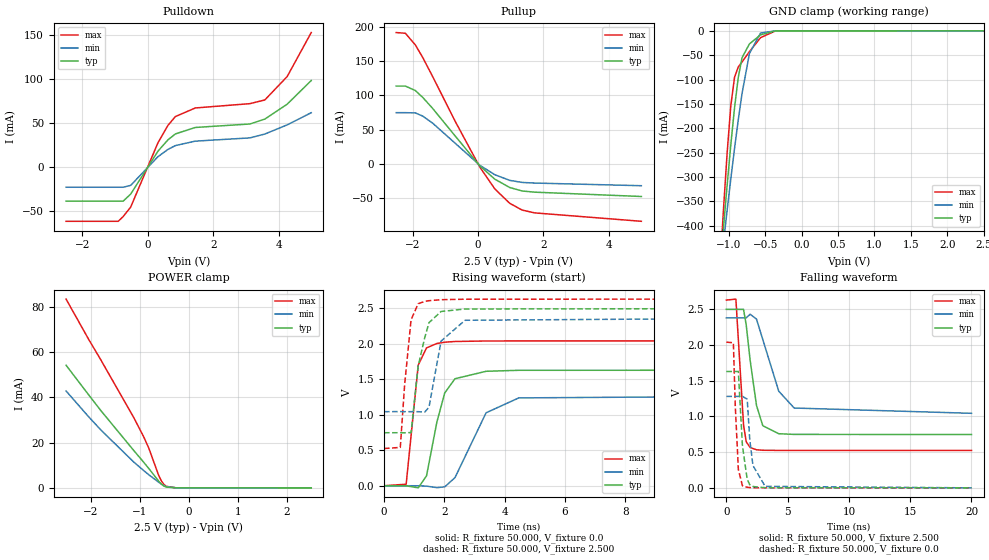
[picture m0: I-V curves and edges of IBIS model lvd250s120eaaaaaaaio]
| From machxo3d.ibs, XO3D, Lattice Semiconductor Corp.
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|   Model lvd250s120eaaaaaaaio
[Model] lvd250s120eaaaaaaaio
Model_type I/O
Polarity   Non-Inverting
Enable   Active-Low
Vinl =  0.700V
Vinh =  1.700V
Vmeas =  1.250V
Cref =  0.0F
Rref =  1.000M
Vref =  0.0V
C_comp   4.200pF   3.800pF   7.500pF
[Temperature Range]   25.000   0.105k   -40.000
[Voltage Range]   2.500V   2.380V   2.630V
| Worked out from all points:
|   slope of the pulldown table from 0 to 0.375 V, typ, clamps not added: 18.1 ohm
|   slope of the pullup table from 0 to 0.375 V, typ, clamps not added: 21.7 ohm
|   GND clamp passes 1 mA (typ) near -0.43 V on its own axis
|   POWER clamp passes 1 mA (typ) near -0.52 V on its own axis
|   rising waveform, R_fixture 50.000, V_fixture 0.0: 20-80 % time 504ps typ, 874ps min, 258ps max; typ from 0 V to 1.63 V
|   rising waveform, R_fixture 50.000, V_fixture 2.500: 20-80 % time 386ps typ, 429ps min, 255ps max; typ from 0.747 V to 2.5 V
|   falling waveform, R_fixture 50.000, V_fixture 2.500: 20-80 % time 818ps typ, 1.5ns min, 419ps max; typ from 2.5 V to 0.747 V
|   falling waveform, R_fixture 50.000, V_fixture 0.0: 20-80 % time 428ps typ, 467ps min, 289ps max; typ from 1.63 V to 0 V
[Pulldown]
|Voltage   I(typ)   I(min)   I(max)
-2.5V     -39.23mA   -23.44mA   -62.24mA
-904mV    -39.23mA   -23.44mA   -62.24mA
-752mV    -39.23mA   -23.44mA   -56.76mA
-524mV    -31.23mA   -21.33mA   -46.02mA
312mV     17.71mA    11.41mA    27.31mA
616mV     30.54mA    19.66mA    47.03mA
844mV     37.3mA     24.02mA    57.11mA
1.452V    44.67mA    29.09mA    66.89mA
3.124V    48.63mA    32.8mA     71.81mA
3.58V     54.23mA    37.18mA    76.01mA
4.264V    71.21mA    47.63mA    102.7mA
5V        98.15mA    61.49mA    152.8mA
[Pullup]
|Voltage   I(typ)   I(min)   I(max)
-2.5V     113.7mA    74.79mA    192mA
-2.22V    113.7mA    74.79mA    191mA
-1.916V   107.2mA    74.48mA    174mA
-1.688V   97.1mA     69.74mA    155.5mA
-1.384V   80.94mA    59.41mA    127.5mA
-700mV    40.9mA     30.22mA    62.53mA
60mV      -3.106mA   -2.235mA   -5.004mA
516mV     -22.49mA   -15.98mA   -36.74mA
972mV     -34.71mA   -24.25mA   -57.81mA
1.352V    -39.8mA    -27.28mA   -67.72mA
1.732V    -41.53mA   -28.21mA   -71.84mA
5V        -47.87mA   -32.1mA    -84.17mA
[GND_clamp]
|Voltage   I(typ)   I(min)   I(max)
-2.5V     -3.262A    -2.545A    -4.485A
-1.123V   -498.5mA   -505.1mA   -498.3mA
-1.072V   -406.1mA   -436mA     -369.4mA
-1.021V   -317.1mA   -368.7mA   -251mA
-970mV    -233.3mA   -303.5mA   -153.4mA
-919mV    -157.7mA   -241.1mA   -95.21mA
-868mV    -95.78mA   -182.7mA   -74.26mA
-817mV    -55.48mA   -129.4mA   -63.96mA
-715mV    -26.89mA   -46.57mA   -42.82mA
-562mV    -8.195mA   -4.484mA   -13.98mA
-358mV    -153.4uA   -68.26uA   -250.2uA
2.5V      0A         0A         0A
[POWER_clamp]
|Voltage   I(typ)   I(min)   I(max)
-2.5V     54.23mA    42.85mA    83.47mA
-2.039V   41.12mA    31.42mA    65.66mA
-1.784V   33.99mA    25.46mA    56.34mA
-1.121V   16.56mA    11.45mA    31.14mA
-917mV    11.31mA    7.645mA    22.57mA
-815mV    8.625mA    5.831mA    17.67mA
-611mV    2.953mA    2.495mA    5.465mA
-560mV    1.702mA    1.758mA    3.215mA
-509mV    833.1uA    1.093mA    1.608mA
-458mV    359uA      552.7uA    679.3uA
-254mV    7.444uA    6.928uA    15.57uA
2.5V      0A         0A         3.059nA
[Ramp]
| variable   typ   min   max
dV/dt_r   0.978/0.506n   0.769/0.880n   1.225/0.256n
dV/dt_f   1.052/0.820n   0.801/1.483n   1.263/0.420n
R_load = 50.000
[Rising Waveform]
R_fixture= 50.000
V_fixture= 0.0
V_fixture_min= 0.0
V_fixture_max= 0.0
|time   V(typ)   V(min)   V(max)
0s        7.849nV    52.32nV    23.6nV
736ps     -521.9uV   1.786uV    21.37mV
1.137ns   -29.85mV   -309.7uV   1.701V
1.411ns   139.6mV    -5.406mV   1.943V
1.754ns   897.2mV    -26.89mV   2.005V
2.014ns   1.307V     -15.69mV   2.023V
2.354ns   1.508V     114.1mV    2.033V
3.385ns   1.613V     1.028V     2.04V
4.469ns   1.627V     1.238V     2.041V
20ns      1.629V     1.281V     2.041V
[Rising Waveform]
R_fixture= 50.000
V_fixture= 2.500
V_fixture_min= 2.380
V_fixture_max= 2.630
|time   V(typ)   V(min)   V(max)
0s        747.2mV    1.044V     524.3mV
542ps     747.2mV    1.045V     540.1mV
686ps     746.2mV    1.044V     1.426V
899ps     749.2mV    1.044V     2.338V
1.133ns   1.686V     1.044V     2.565V
1.35ns    2.083V     1.037V     2.598V
1.493ns   2.299V     1.108V     2.608V
1.894ns   2.456V     2.039V     2.622V
2.688ns   2.491V     2.332V     2.629V
20ns      2.5V       2.38V      2.63V
[Falling Waveform]
R_fixture= 50.000
V_fixture= 2.500
V_fixture_min= 2.380
V_fixture_max= 2.630
|time   V(typ)   V(min)   V(max)
0s        2.5V       2.38V      2.63V
779ps     2.499V     2.38V      2.643V
1.404ns   2.5V       2.381V     880.1mV
1.622ns   2.281V     2.381V     646mV
1.942ns   1.787V     2.432V     565mV
2.461ns   1.154V     2.363V     533.3mV
2.973ns   871.1mV    2.078V     526.5mV
4.275ns   758.1mV    1.354V     524.4mV
5.533ns   748.7mV    1.118V     524.3mV
20ns      747.1mV    1.044V     524.3mV
[Falling Waveform]
R_fixture= 50.000
V_fixture= 0.0
V_fixture_min= 0.0
V_fixture_max= 0.0
|time   V(typ)   V(min)   V(max)
0s        1.629V     1.281V     2.041V
574ps     1.629V     1.281V     2.032V
728ps     1.629V     1.281V     1.157V
980ps     1.631V     1.281V     259mV
1.312ns   591.1mV    1.282V     29.84mV
1.705ns   117.8mV    1.242V     8.573mV
1.912ns   43.16mV    673.2mV    4.592mV
2.173ns   18.74mV    311.6mV    2.19mV
3.169ns   2.508mV    21.03mV    172uV
20ns      27.28nV    114nV      82.28nV
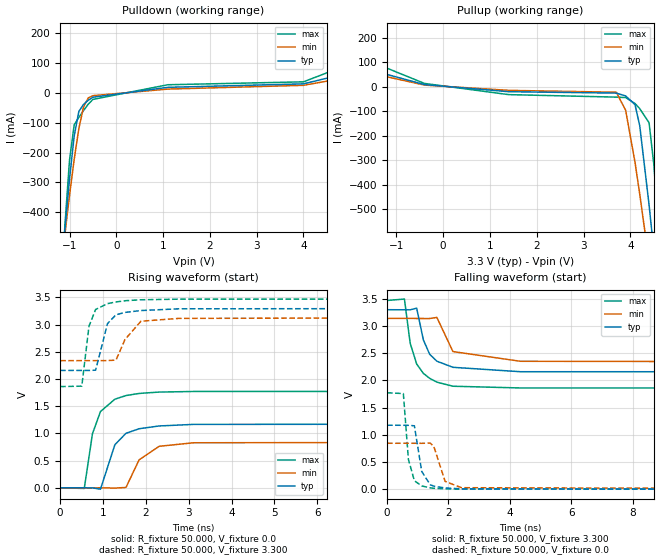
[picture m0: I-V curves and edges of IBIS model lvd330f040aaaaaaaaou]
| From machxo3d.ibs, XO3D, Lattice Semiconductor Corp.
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|   Model lvd330f040aaaaaaaaou
[Model] lvd330f040aaaaaaaaou
Model_type Output
Polarity   Non-Inverting
Enable   Active-High
Vmeas =  1.650V
Cref =  0.0F
Rref =  1.000M
Vref =  0.0V
C_comp   4.200pF   3.800pF   7.500pF
[Temperature Range]   25.000   0.105k   -40.000
[Voltage Range]   3.300V   3.140V   3.470V
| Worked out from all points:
|   slope of the pulldown table from 0 to 0.495 V, typ, clamps not added: 48.6 ohm
|   slope of the pullup table from 0 to 0.495 V, typ, clamps not added: 53.4 ohm
|   rising waveform, R_fixture 50.000, V_fixture 0.0: 20-80 % time 381ps typ, 427ps min, 320ps max; typ from 0 V to 1.18 V
|   rising waveform, R_fixture 50.000, V_fixture 3.300: 20-80 % time 227ps typ, 310ps min, 163ps max; typ from 2.16 V to 3.3 V
|   falling waveform, R_fixture 50.000, V_fixture 3.300: 20-80 % time 480ps typ, 502ps min, 459ps max; typ from 3.3 V to 2.16 V
|   falling waveform, R_fixture 50.000, V_fixture 0.0: 20-80 % time 213ps typ, 282ps min, 168ps max; typ from 1.18 V to 0 V
[Pulldown]
|Voltage   I(typ)   I(min)   I(max)
-3.3V     -4.914A    -3.768A    -6.865A
-1.1V     -459.8mA   -475.4mA   -447.6mA
-1V       -288.2mA   -343.8mA   -225.5mA
-900mV    -144.4mA   -222.4mA   -107.3mA
-800mV    -62mA      -119.3mA   -81.84mA
-700mV    -38.56mA   -46.76mA   -59.22mA
-600mV    -24.6mA    -17.1mA    -38.05mA
-500mV    -14.61mA   -9.377mA   -21.94mA
1.1V      18.49mA    12.63mA    27.15mA
4V        30.15mA    25.25mA    36.93mA
5.3V      79.41mA    61.48mA    115.2mA
6.6V      142.9mA    104.5mA    217.4mA
[Pullup]
|Voltage   I(typ)   I(min)   I(max)
-3.3V     159.4mA    129.8mA    239.8mA
-400mV    9.016mA    6.977mA    13.78mA
1.4V      -20.07mA   -14.6mA    -32.02mA
3.7V      -25.83mA   -22.27mA   -42.22mA
3.9V      -37.55mA   -96.42mA   -44mA
4.1V      -73.11mA   -309.2mA   -68.45mA
4.2V      -158.5mA   -438.3mA   -89.1mA
4.4V      -482.5mA   -714.8mA   -147.1mA
4.5V      -668.5mA   -858mA     -314.3mA
4.6V      -860.5mA   -1.003A    -560.2mA
4.7V      -1.056A    -1.15A     -829.1mA
6.6V      -4.941A    -4.033A    -6.405A
[Ramp]
| variable   typ   min   max
dV/dt_r   0.705/0.381n   0.507/0.413n   1.064/0.320n
dV/dt_f   0.685/0.476n   0.481/0.492n   0.965/0.458n
R_load = 50.000
[Rising Waveform]
R_fixture= 50.000
V_fixture= 0.0
V_fixture_min= 0.0
V_fixture_max= 0.0
|time   V(typ)   V(min)   V(max)
0s        43.91nV    99.25nV    528.4nV
563ps     -19.76uV   61.93uV    -11.47mV
754ps     -1.559mV   8.947uV    994.1mV
941ps     -24.92mV   -15.78uV   1.402V
1.277ns   792.4mV    -4.864mV   1.629V
1.536ns   1.002V     6.275mV    1.696V
1.842ns   1.086V     513.7mV    1.735V
2.309ns   1.137V     763mV      1.76V
3.112ns   1.166V     828.1mV    1.771V
20ns      1.176V     844.4mV    1.773V
[Rising Waveform]
R_fixture= 50.000
V_fixture= 3.300
V_fixture_min= 3.140
V_fixture_max= 3.470
|time   V(typ)   V(min)   V(max)
0s        2.158V     2.338V     1.861V
505ps     2.158V     2.338V     1.869V
673ps     2.157V     2.338V     2.972V
828ps     2.163V     2.338V     3.279V
1.105ns   3.019V     2.339V     3.386V
1.303ns   3.181V     2.348V     3.417V
1.514ns   3.225V     2.728V     3.439V
1.885ns   3.259V     3.062V     3.457V
2.77ns    3.291V     3.115V     3.468V
20ns      3.3V       3.14V      3.47V
[Falling Waveform]
R_fixture= 50.000
V_fixture= 3.300
V_fixture_min= 3.140
V_fixture_max= 3.470
|time   V(typ)   V(min)   V(max)
0s        3.3V       3.14V      3.47V
567ps     3.299V     3.14V      3.496V
754ps     3.298V     3.14V      2.683V
965ps     3.329V     3.139V     2.303V
1.184ns   2.745V     3.138V     2.129V
1.387ns   2.482V     3.138V     2.039V
1.624ns   2.353V     3.158V     1.968V
2.146ns   2.241V     2.53V      1.893V
4.343ns   2.16V      2.352V     1.861V
20ns      2.158V     2.338V     1.861V
[Falling Waveform]
R_fixture= 50.000
V_fixture= 0.0
V_fixture_min= 0.0
V_fixture_max= 0.0
|time   V(typ)   V(min)   V(max)
0s        1.176V     844.4mV    1.773V
532ps     1.175V     844.4mV    1.758V
696ps     1.174V     844.5mV    547.4mV
891ps     1.165V     844.2mV    155.5mV
1.13ns    325.9mV    843.4mV    59.13mV
1.406ns   82.06mV    847.4mV    24.19mV
1.524ns   55.06mV    784.3mV    17.12mV
1.892ns   21.24mV    143.4mV    5.604mV
2.424ns   6.413mV    26.97mV    1.134mV
20ns      43.65nV    98.13nV    616.1nV
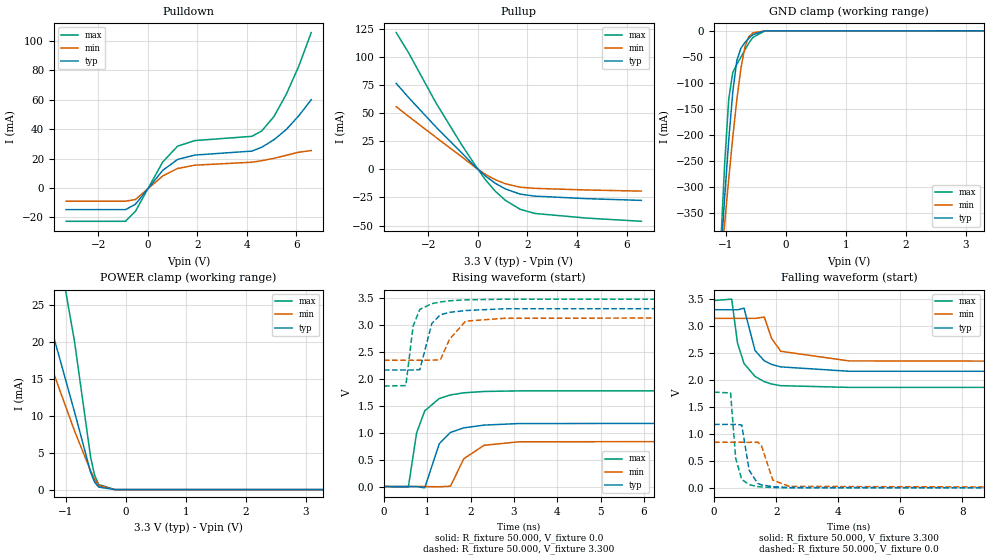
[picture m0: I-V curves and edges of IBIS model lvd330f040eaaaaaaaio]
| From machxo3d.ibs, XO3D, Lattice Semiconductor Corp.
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|   Model lvd330f040eaaaaaaaio
[Model] lvd330f040eaaaaaaaio
Model_type I/O
Polarity   Non-Inverting
Enable   Active-Low
Vinl =  0.800V
Vinh =  2.000V
Vmeas =  1.650V
Cref =  0.0F
Rref =  1.000M
Vref =  0.0V
C_comp   4.200pF   3.800pF   7.500pF
[Temperature Range]   25.000   0.105k   -40.000
[Voltage Range]   3.300V   3.140V   3.470V
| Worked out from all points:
|   slope of the pulldown table from 0 to 0.495 V, typ, clamps not added: 48.6 ohm
|   slope of the pullup table from 0 to 0.495 V, typ, clamps not added: 53.4 ohm
|   GND clamp passes 1 mA (typ) near -0.43 V on its own axis
|   POWER clamp passes 1 mA (typ) near -0.52 V on its own axis
|   rising waveform, R_fixture 50.000, V_fixture 0.0: 20-80 % time 381ps typ, 427ps min, 320ps max; typ from 0 V to 1.18 V
|   rising waveform, R_fixture 50.000, V_fixture 3.300: 20-80 % time 227ps typ, 310ps min, 163ps max; typ from 2.16 V to 3.3 V
|   falling waveform, R_fixture 50.000, V_fixture 3.300: 20-80 % time 479ps typ, 502ps min, 459ps max; typ from 3.3 V to 2.16 V
|   falling waveform, R_fixture 50.000, V_fixture 0.0: 20-80 % time 213ps typ, 282ps min, 168ps max; typ from 1.18 V to 0 V
[Pulldown]
|Voltage   I(typ)   I(min)   I(max)
-3.3V     -14.66mA   -8.951mA   -22.6mA
-900mV    -14.66mA   -8.951mA   -22.6mA
-500mV    -11.02mA   -7.807mA   -15.8mA
600mV     11.95mA    8.157mA    17.61mA
1.2V      19.4mA     13.27mA    28.41mA
1.9V      22.39mA    15.52mA    32.23mA
4.2V      25.08mA    17.53mA    35.11mA
4.6V      27.7mA     18.56mA    38.76mA
5.1V      32.86mA    20.23mA    48.67mA
5.6V      39.87mA    22.27mA    63.97mA
6.1V      49.11mA    24.33mA    82.87mA
6.6V      60.02mA    25.47mA    105.6mA
[Pullup]
|Voltage   I(typ)   I(min)   I(max)
-3.3V     76.51mA    55.77mA    121.7mA
-2.8V     63.92mA    47.14mA    103.7mA
-1.7V     37.84mA    28.57mA    59.4mA
-700mV    15.71mA    11.97mA    23.38mA
-100mV    2.145mA    1.619mA    3.301mA
300mV     -5.911mA   -4.416mA   -9.19mA
700mV     -12.39mA   -9.179mA   -19.41mA
1.1V      -17.33mA   -12.72mA   -27.42mA
1.7V      -22.01mA   -15.86mA   -35.48mA
2.3V      -23.82mA   -16.89mA   -39.22mA
4.4V      -26.06mA   -18.36mA   -43.36mA
6.6V      -27.59mA   -19.35mA   -46.2mA
[GND_clamp]
|Voltage   I(typ)   I(min)   I(max)
-3.3V     -4.913A    -3.768A    -6.865A
-1.089V   -436.6mA   -458.9mA   -411.5mA
-1.022V   -318.8mA   -370mA     -253.2mA
-955mV    -210mA     -284.8mA   -131.4mA
-888mV    -117.9mA   -205.1mA   -80.02mA
-821mV    -57.76mA   -133.4mA   -64.74mA
-754mV    -33.88mA   -73.63mA   -51.23mA
-687mV    -22.76mA   -31.63mA   -36.92mA
-620mV    -14.21mA   -11.16mA   -23.73mA
-553mV    -7.411mA   -3.893mA   -12.67mA
-352mV    -131.3uA   -58.9uA    -219uA
3.3V      0A         0A         0A
[POWER_clamp]
|Voltage   I(typ)   I(min)   I(max)
-3.3V     82.87mA    74.06mA    118.1mA
-1.926V   41.79mA    34.09mA    64.67mA
-1.725V   35.77mA    28.77mA    56.95mA
-1.658V   33.78mA    27.04mA    54.31mA
-1.189V   20.27mA    15.49mA    35.28mA
-1.122V   18.35mA    13.94mA    32.42mA
-854mV    10.5mA     7.941mA    20.03mA
-586mV    2.349mA    2.531mA    4.384mA
-519mV    997.2uA    1.406mA    1.953mA
-452mV    344.2uA    549.2uA    685.9uA
-184mV    2.187uA    1.695uA    8.906uA
3.3V      0A         0A         0A
[Ramp]
| variable   typ   min   max
dV/dt_r   0.705/0.381n   0.507/0.413n   1.064/0.320n
dV/dt_f   0.685/0.476n   0.481/0.492n   0.965/0.458n
R_load = 50.000
[Rising Waveform]
R_fixture= 50.000
V_fixture= 0.0
V_fixture_min= 0.0
V_fixture_max= 0.0
|time   V(typ)   V(min)   V(max)
0s        43.91nV    99.25nV    528.4nV
563ps     -19.77uV   61.93uV    -11.47mV
754ps     -1.559mV   8.945uV    994.1mV
941ps     -24.92mV   -15.79uV   1.402V
1.277ns   792.4mV    -4.864mV   1.629V
1.536ns   1.002V     6.275mV    1.696V
1.842ns   1.086V     513.7mV    1.735V
2.309ns   1.137V     762.8mV    1.76V
3.112ns   1.166V     828.1mV    1.771V
20ns      1.176V     844.4mV    1.773V
[Rising Waveform]
R_fixture= 50.000
V_fixture= 3.300
V_fixture_min= 3.140
V_fixture_max= 3.470
|time   V(typ)   V(min)   V(max)
0s        2.158V     2.338V     1.861V
505ps     2.158V     2.338V     1.869V
673ps     2.157V     2.338V     2.972V
828ps     2.163V     2.338V     3.279V
1.105ns   3.019V     2.339V     3.386V
1.303ns   3.181V     2.348V     3.417V
1.514ns   3.225V     2.728V     3.439V
1.885ns   3.259V     3.062V     3.457V
2.77ns    3.291V     3.115V     3.468V
20ns      3.3V       3.14V      3.47V
[Falling Waveform]
R_fixture= 50.000
V_fixture= 3.300
V_fixture_min= 3.140
V_fixture_max= 3.470
|time   V(typ)   V(min)   V(max)
0s        3.3V       3.14V      3.47V
567ps     3.299V     3.14V      3.496V
754ps     3.298V     3.14V      2.683V
965ps     3.329V     3.139V     2.303V
1.32ns    2.544V     3.139V     2.064V
1.618ns   2.353V     3.162V     1.967V
1.853ns   2.286V     2.769V     1.923V
2.147ns   2.241V     2.53V      1.893V
4.343ns   2.16V      2.352V     1.861V
20ns      2.158V     2.338V     1.861V
[Falling Waveform]
R_fixture= 50.000
V_fixture= 0.0
V_fixture_min= 0.0
V_fixture_max= 0.0
|time   V(typ)   V(min)   V(max)
0s        1.176V     844.4mV    1.773V
532ps     1.175V     844.4mV    1.758V
696ps     1.174V     844.5mV    547.4mV
891ps     1.165V     844.2mV    155.5mV
1.13ns    325.9mV    843.4mV    59.13mV
1.406ns   82.06mV    847.4mV    24.19mV
1.524ns   55.06mV    784.3mV    17.12mV
1.892ns   21.24mV    143.4mV    5.604mV
2.424ns   6.413mV    26.97mV    1.134mV
20ns      43.65nV    98.13nV    616.1nV
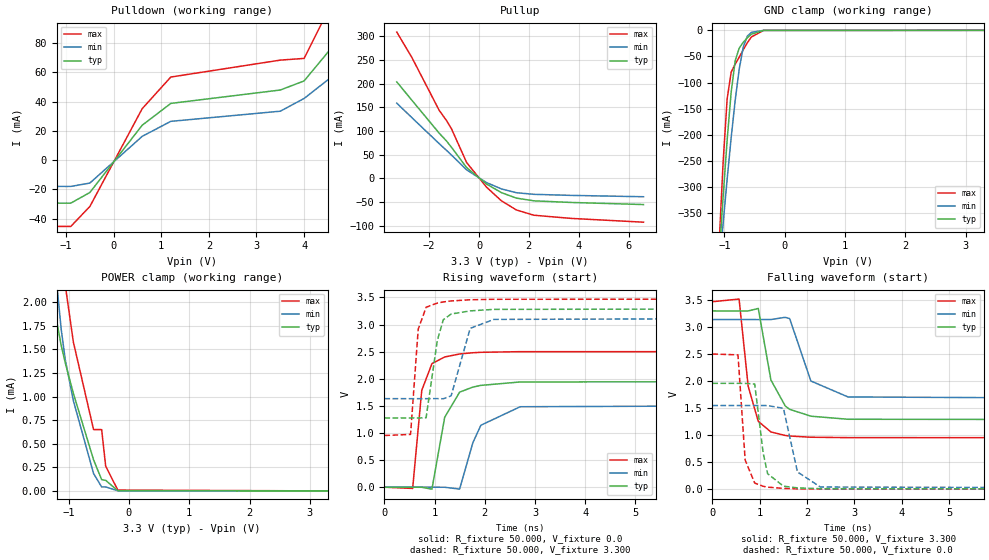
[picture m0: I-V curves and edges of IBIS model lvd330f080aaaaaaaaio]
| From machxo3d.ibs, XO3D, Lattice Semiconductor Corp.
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|   Model lvd330f080aaaaaaaaio
[Model] lvd330f080aaaaaaaaio
Model_type I/O
Polarity   Non-Inverting
Enable   Active-Low
Vinl =  0.800V
Vinh =  2.000V
Vmeas =  1.650V
Cref =  0.0F
Rref =  1.000M
Vref =  0.0V
C_comp   4.200pF   3.800pF   7.500pF
[Temperature Range]   25.000   0.105k   -40.000
[Voltage Range]   3.300V   3.140V   3.470V
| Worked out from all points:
|   slope of the pulldown table from 0 to 0.495 V, typ, clamps not added: 24.3 ohm
|   slope of the pullup table from 0 to 0.495 V, typ, clamps not added: 26.7 ohm
|   GND clamp passes 1 mA (typ) near -0.43 V on its own axis
|   POWER clamp passes 1 mA (typ) near -0.91 V on its own axis
|   rising waveform, R_fixture 50.000, V_fixture 0.0: 20-80 % time 278ps typ, 380ps min, 173ps max; typ from 0 V to 1.96 V
|   rising waveform, R_fixture 50.000, V_fixture 3.300: 20-80 % time 171ps typ, 252ps min, 106ps max; typ from 1.28 V to 3.3 V
|   falling waveform, R_fixture 50.000, V_fixture 3.300: 20-80 % time 346ps typ, 430ps min, 243ps max; typ from 3.3 V to 1.28 V
|   falling waveform, R_fixture 50.000, V_fixture 0.0: 20-80 % time 157ps typ, 226ps min, 112ps max; typ from 1.96 V to 0 V
[Pulldown]
|Voltage   I(typ)   I(min)   I(max)
-3.3V     -29.32mA   -17.9mA    -45.21mA
-900mV    -29.32mA   -17.9mA    -45.21mA
-500mV    -22.04mA   -15.61mA   -31.59mA
600mV     23.9mA     16.31mA    35.23mA
1.2V      38.8mA     26.54mA    56.81mA
3.5V      47.95mA    33.48mA    68.37mA
4V        54.16mA    42.19mA    69.53mA
4.6V      77.69mA    57.45mA    108.5mA
5V        92.26mA    69.04mA    126.1mA
5.3V      106.5mA    79.07mA    149.7mA
5.9V      142.1mA    101.9mA    208.2mA
6.6V      192.2mA    131.4mA    293.8mA
[Pullup]
|Voltage   I(typ)   I(min)   I(max)
-3.3V     203.7mA    158.8mA    308.8mA
-2.7V     165.3mA    128.5mA    255.8mA
-1.6V     95.59mA    73.49mA    143.8mA
-1.3V     78.7mA     58.94mA    121.7mA
-1.1V     65.29mA    49.09mA    104.2mA
-500mV    22.96mA    18.15mA    33.78mA
300mV     -11.82mA   -8.831mA   -18.38mA
900mV     -30.09mA   -22.2mA    -47.37mA
1.5V      -41.6mA    -30.18mA   -66.6mA
2.2V      -47.32mA   -33.59mA   -77.7mA
3.7V      -50.76mA   -35.84mA   -84.41mA
6.6V      -55.18mA   -38.69mA   -92.4mA
[GND_clamp]
|Voltage   I(typ)   I(min)   I(max)
-3.3V     -4.913A    -3.768A    -6.865A
-1.089V   -436.6mA   -458.9mA   -411.5mA
-1.022V   -318.8mA   -370mA     -253.2mA
-955mV    -210mA     -284.8mA   -131.4mA
-888mV    -117.9mA   -205.1mA   -80.02mA
-821mV    -57.76mA   -133.4mA   -64.74mA
-754mV    -33.88mA   -73.63mA   -51.23mA
-687mV    -22.76mA   -31.63mA   -36.92mA
-620mV    -14.21mA   -11.16mA   -23.73mA
-553mV    -7.411mA   -3.893mA   -12.67mA
-352mV    -131.3uA   -58.9uA    -219uA
3.3V      0A         0A         0A
[POWER_clamp]
|Voltage   I(typ)   I(min)   I(max)
-3.3V     32.67mA    26.87mA    52.85mA
-1.323V   2.804mA    3.246mA    8.665mA
-1.256V   2.134mA    2.67mA     6.124mA
-1.189V   1.77mA     2.147mA    4.184mA
-1.122V   1.54mA     1.71mA     2.893mA
-1.055V   1.357mA    1.39mA     2.18mA
-921mV    1.034mA    956.5uA    1.578mA
-586mV    330uA      184.5uA    649.8uA
-452mV    119.7uA    42.63uA    649.8uA
-385mV    112.2uA    42.63uA    262.6uA
-184mV    2.18uA     1.689uA    8.903uA
3.3V      0A         0A         0A
[Ramp]
| variable   typ   min   max
dV/dt_r   1.175/0.279n   0.929/0.380n   1.501/0.172n
dV/dt_f   1.213/0.346n   0.904/0.422n   1.510/0.242n
R_load = 50.000
[Rising Waveform]
R_fixture= 50.000
V_fixture= 0.0
V_fixture_min= 0.0
V_fixture_max= 0.0
|time   V(typ)   V(min)   V(max)
0s        28.46nV    68.59nV    322.9nV
562ps     -33uV      4.673uV    -22.51mV
743ps     -1.105mV   4.673uV    1.785V
946ps     -36.14mV   -97.91uV   2.279V
1.2ns     1.289V     -837.4uV   2.402V
1.497ns   1.753V     -34.47mV   2.457V
1.762ns   1.847V     822.3mV    2.48V
1.921ns   1.878V     1.143V     2.488V
2.703ns   1.941V     1.484V     2.5V
20ns      1.959V     1.548V     2.502V
[Rising Waveform]
R_fixture= 50.000
V_fixture= 3.300
V_fixture_min= 3.140
V_fixture_max= 3.470
|time   V(typ)   V(min)   V(max)
0s        1.278V     1.633V     953.3mV
520ps     1.278V     1.633V     973.7mV
673ps     1.277V     1.633V     2.915V
830ps     1.281V     1.633V     3.319V
1.052ns   2.7V       1.634V     3.396V
1.172ns   3.088V     1.631V     3.417V
1.328ns   3.194V     1.685V     3.435V
1.708ns   3.252V     2.93V      3.457V
2.181ns   3.28V      3.095V     3.466V
20ns      3.3V       3.14V      3.47V
[Falling Waveform]
R_fixture= 50.000
V_fixture= 3.300
V_fixture_min= 3.140
V_fixture_max= 3.470
|time   V(typ)   V(min)   V(max)
0s        3.3V       3.14V      3.47V
564ps     3.299V     3.14V      3.519V
756ps     3.299V     3.14V      1.904V
969ps     3.345V     3.139V     1.256V
1.236ns   2.021V     3.14V      1.059V
1.538ns   1.54V      3.181V     994mV
1.632ns   1.478V     3.157V     983.7mV
2.079ns   1.351V     2.002V     961.5mV
2.864ns   1.294V     1.707V     954mV
20ns      1.278V     1.633V     953.2mV
[Falling Waveform]
R_fixture= 50.000
V_fixture= 0.0
V_fixture_min= 0.0
V_fixture_max= 0.0
|time   V(typ)   V(min)   V(max)
0s        1.959V     1.548V     2.502V
541ps     1.959V     1.548V     2.486V
692ps     1.958V     1.548V     538.1mV
894ps     1.947V     1.548V     113.4mV
1.072ns   670.5mV    1.548V     53.11mV
1.166ns   287.5mV    1.547V     37.74mV
1.5ns     54.98mV    1.497V     13.75mV
1.796ns   24.25mV    318.6mV    4.998mV
2.281ns   8.516mV    39.57mV    1.074mV
20ns      38.52nV    73.76nV    488.4nV
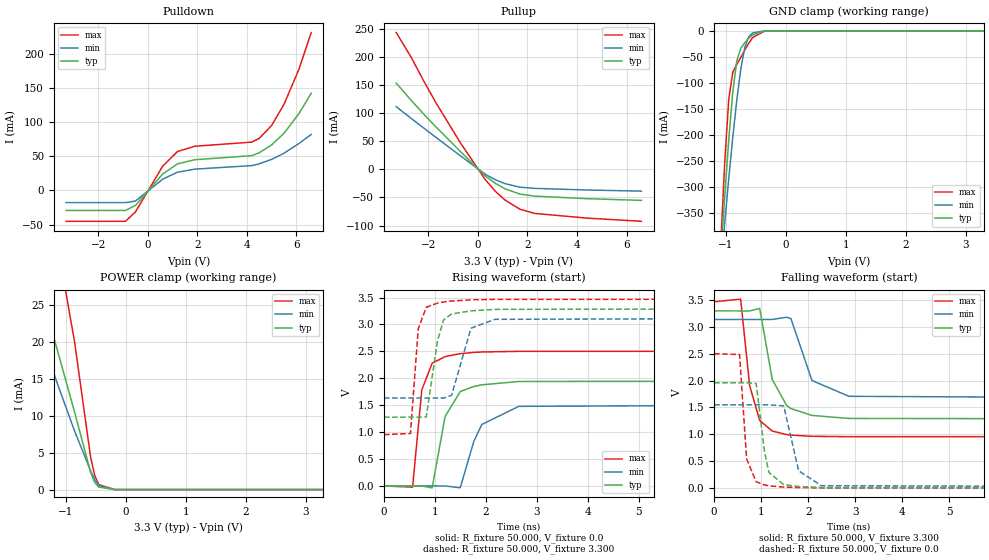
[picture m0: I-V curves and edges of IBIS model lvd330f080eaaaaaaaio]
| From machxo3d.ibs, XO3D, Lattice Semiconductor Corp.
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|   Model lvd330f080eaaaaaaaio
[Model] lvd330f080eaaaaaaaio
Model_type I/O
Polarity   Non-Inverting
Enable   Active-Low
Vinl =  0.800V
Vinh =  2.000V
Vmeas =  1.650V
Cref =  0.0F
Rref =  1.000M
Vref =  0.0V
C_comp   4.200pF   3.800pF   7.500pF
[Temperature Range]   25.000   0.105k   -40.000
[Voltage Range]   3.300V   3.140V   3.470V
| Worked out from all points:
|   slope of the pulldown table from 0 to 0.495 V, typ, clamps not added: 24.3 ohm
|   slope of the pullup table from 0 to 0.495 V, typ, clamps not added: 26.7 ohm
|   GND clamp passes 1 mA (typ) near -0.43 V on its own axis
|   POWER clamp passes 1 mA (typ) near -0.52 V on its own axis
|   rising waveform, R_fixture 50.000, V_fixture 0.0: 20-80 % time 278ps typ, 380ps min, 173ps max; typ from 0 V to 1.96 V
|   rising waveform, R_fixture 50.000, V_fixture 3.300: 20-80 % time 171ps typ, 252ps min, 106ps max; typ from 1.28 V to 3.3 V
|   falling waveform, R_fixture 50.000, V_fixture 3.300: 20-80 % time 346ps typ, 430ps min, 243ps max; typ from 3.3 V to 1.28 V
|   falling waveform, R_fixture 50.000, V_fixture 0.0: 20-80 % time 157ps typ, 226ps min, 112ps max; typ from 1.96 V to 0 V
[Pulldown]
|Voltage   I(typ)   I(min)   I(max)
-3.3V     -29.32mA   -17.9mA    -45.21mA
-900mV    -29.32mA   -17.9mA    -45.21mA
-500mV    -22.04mA   -15.61mA   -31.59mA
600mV     23.9mA     16.31mA    35.23mA
1.2V      38.8mA     26.54mA    56.81mA
1.9V      44.78mA    31.05mA    64.46mA
4.2V      50.68mA    36.17mA    70.51mA
4.5V      54.92mA    38.85mA    75.97mA
5V        66.42mA    45.26mA    94.78mA
5.5V      83.38mA    54.27mA    125.7mA
6.1V      112mA      68.39mA    176.7mA
6.6V      142mA      81.7mA     230.6mA
[Pullup]
|Voltage   I(typ)   I(min)   I(max)
-3.3V     153.5mA    111.6mA    243.5mA
-2.7V     123.2mA    90.93mA    199.9mA
-2.2V     98.95mA    73.93mA    158.2mA
-1.7V     75.72mA    57.16mA    118.9mA
-700mV    31.42mA    23.93mA    46.77mA
300mV     -11.82mA   -8.831mA   -18.38mA
700mV     -24.77mA   -18.36mA   -38.83mA
1.1V      -34.65mA   -25.44mA   -54.83mA
1.7V      -44.02mA   -31.73mA   -70.96mA
2.3V      -47.65mA   -33.78mA   -78.43mA
4.4V      -52.12mA   -36.72mA   -86.71mA
6.6V      -55.18mA   -38.69mA   -92.4mA
[GND_clamp]
|Voltage   I(typ)   I(min)   I(max)
-3.3V     -4.913A    -3.768A    -6.865A
-1.089V   -436.6mA   -458.9mA   -411.5mA
-1.022V   -318.8mA   -370mA     -253.2mA
-955mV    -210mA     -284.8mA   -131.4mA
-888mV    -117.9mA   -205.1mA   -80.02mA
-821mV    -57.76mA   -133.4mA   -64.74mA
-754mV    -33.88mA   -73.63mA   -51.23mA
-687mV    -22.76mA   -31.63mA   -36.92mA
-620mV    -14.21mA   -11.16mA   -23.73mA
-553mV    -7.411mA   -3.893mA   -12.67mA
-352mV    -131.3uA   -58.9uA    -219uA
3.3V      0A         0A         0A
[POWER_clamp]
|Voltage   I(typ)   I(min)   I(max)
-3.3V     82.87mA    74.06mA    118.1mA
-1.926V   41.79mA    34.09mA    64.67mA
-1.725V   35.77mA    28.77mA    56.95mA
-1.658V   33.78mA    27.04mA    54.31mA
-1.189V   20.27mA    15.49mA    35.28mA
-1.122V   18.35mA    13.94mA    32.42mA
-854mV    10.5mA     7.941mA    20.03mA
-586mV    2.349mA    2.531mA    4.384mA
-519mV    997.2uA    1.406mA    1.953mA
-452mV    344.2uA    549.2uA    685.9uA
-184mV    2.187uA    1.695uA    8.906uA
3.3V      0A         0A         0A
[Ramp]
| variable   typ   min   max
dV/dt_r   1.175/0.279n   0.929/0.380n   1.501/0.172n
dV/dt_f   1.213/0.346n   0.904/0.422n   1.510/0.242n
R_load = 50.000
[Rising Waveform]
R_fixture= 50.000
V_fixture= 0.0
V_fixture_min= 0.0
V_fixture_max= 0.0
|time   V(typ)   V(min)   V(max)
0s        28.46nV    68.59nV    322.9nV
562ps     -33.01uV   4.672uV    -22.51mV
743ps     -1.105mV   4.672uV    1.785V
946ps     -36.14mV   -97.91uV   2.279V
1.2ns     1.289V     -837.4uV   2.402V
1.497ns   1.753V     -34.47mV   2.457V
1.762ns   1.847V     822.3mV    2.48V
1.92ns    1.878V     1.141V     2.488V
2.646ns   1.94V      1.478V     2.5V
20ns      1.959V     1.548V     2.502V
[Rising Waveform]
R_fixture= 50.000
V_fixture= 3.300
V_fixture_min= 3.140
V_fixture_max= 3.470
|time   V(typ)   V(min)   V(max)
0s        1.278V     1.633V     953.3mV
520ps     1.278V     1.633V     973.7mV
673ps     1.277V     1.633V     2.915V
830ps     1.281V     1.633V     3.319V
1.052ns   2.7V       1.634V     3.396V
1.172ns   3.088V     1.631V     3.417V
1.328ns   3.194V     1.685V     3.435V
1.708ns   3.252V     2.93V      3.457V
2.181ns   3.28V      3.095V     3.466V
20ns      3.3V       3.14V      3.47V
[Falling Waveform]
R_fixture= 50.000
V_fixture= 3.300
V_fixture_min= 3.140
V_fixture_max= 3.470
|time   V(typ)   V(min)   V(max)
0s        3.3V       3.14V      3.47V
564ps     3.299V     3.14V      3.519V
756ps     3.299V     3.14V      1.904V
969ps     3.345V     3.139V     1.256V
1.236ns   2.021V     3.14V      1.059V
1.538ns   1.54V      3.181V     994mV
1.632ns   1.478V     3.157V     983.7mV
2.079ns   1.351V     2.002V     961.5mV
2.864ns   1.294V     1.707V     954mV
20ns      1.278V     1.633V     953.2mV
[Falling Waveform]
R_fixture= 50.000
V_fixture= 0.0
V_fixture_min= 0.0
V_fixture_max= 0.0
|time   V(typ)   V(min)   V(max)
0s        1.959V     1.548V     2.502V
541ps     1.959V     1.548V     2.486V
692ps     1.958V     1.548V     538.1mV
894ps     1.947V     1.548V     113.4mV
1.072ns   670.5mV    1.548V     53.11mV
1.166ns   287.5mV    1.547V     37.74mV
1.479ns   59.16mV    1.529V     14.6mV
1.796ns   24.25mV    318.6mV    4.998mV
2.281ns   8.516mV    39.57mV    1.074mV
20ns      38.52nV    73.76nV    488.4nV
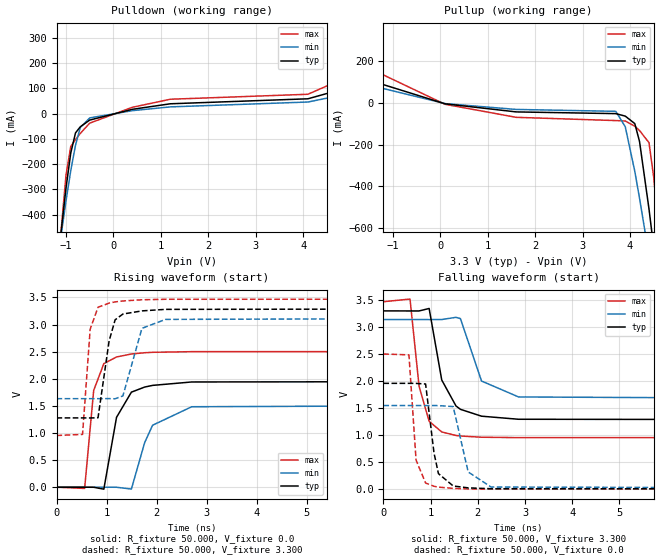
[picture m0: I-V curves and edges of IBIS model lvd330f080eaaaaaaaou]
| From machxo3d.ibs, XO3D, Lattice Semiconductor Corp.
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|   Model lvd330f080eaaaaaaaou
[Model] lvd330f080eaaaaaaaou
Model_type Output
Polarity   Non-Inverting
Enable   Active-High
Vmeas =  1.650V
Cref =  0.0F
Rref =  1.000M
Vref =  0.0V
C_comp   4.200pF   3.800pF   7.500pF
[Temperature Range]   25.000   0.105k   -40.000
[Voltage Range]   3.300V   3.140V   3.470V
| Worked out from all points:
|   slope of the pulldown table from 0 to 0.495 V, typ, clamps not added: 24.3 ohm
|   slope of the pullup table from 0 to 0.495 V, typ, clamps not added: 26.7 ohm
|   rising waveform, R_fixture 50.000, V_fixture 0.0: 20-80 % time 278ps typ, 380ps min, 173ps max; typ from 0 V to 1.96 V
|   rising waveform, R_fixture 50.000, V_fixture 3.300: 20-80 % time 171ps typ, 252ps min, 106ps max; typ from 1.28 V to 3.3 V
|   falling waveform, R_fixture 50.000, V_fixture 3.300: 20-80 % time 346ps typ, 430ps min, 243ps max; typ from 3.3 V to 1.28 V
|   falling waveform, R_fixture 50.000, V_fixture 0.0: 20-80 % time 157ps typ, 226ps min, 112ps max; typ from 1.96 V to 0 V
[Pulldown]
|Voltage   I(typ)   I(min)   I(max)
-3.3V     -4.914A    -3.768A    -6.866A
-1.1V     -463.2mA   -477mA     -456mA
-1V       -294.6mA   -346mA     -243.6mA
-900mV    -156.2mA   -226mA     -129.9mA
-800mV    -76.66mA   -125.5mA   -103mA
-700mV    -52.48mA   -55.46mA   -78.79mA
-500mV    -25.63mA   -17.18mA   -37.74mA
400mV     16.94mA    11.56mA    24.96mA
1.2V      38.8mA     26.54mA    56.81mA
4.1V      58.57mA    45.76mA    76.5mA
5.4V      126.5mA    95.51mA    183.4mA
6.6V      224.8mA    160.8mA    342.4mA
[Pullup]
|Voltage   I(typ)   I(min)   I(max)
-3.3V     236.4mA    185.7mA    361.6mA
100mV     -4.146mA   -3.108mA   -6.422mA
1.6V      -42.9mA    -31.02mA   -68.91mA
3.7V      -51.21mA   -40.19mA   -84.43mA
3.9V      -63.12mA   -114.5mA   -86.54mA
4.1V      -98.87mA   -327.4mA   -111.3mA
4.2V      -184.4mA   -456.5mA   -132.1mA
4.4V      -508.6mA   -733.1mA   -190.5mA
4.5V      -694.7mA   -876.4mA   -357.9mA
4.6V      -886.7mA   -1.022A    -603.9mA
4.7V      -1.083A    -1.169A    -873mA
6.6V      -4.969A    -4.052A    -6.451A
[Ramp]
| variable   typ   min   max
dV/dt_r   1.175/0.279n   0.929/0.380n   1.501/0.172n
dV/dt_f   1.213/0.346n   0.904/0.422n   1.510/0.242n
R_load = 50.000
[Rising Waveform]
R_fixture= 50.000
V_fixture= 0.0
V_fixture_min= 0.0
V_fixture_max= 0.0
|time   V(typ)   V(min)   V(max)
0s        28.46nV    68.59nV    322.9nV
562ps     -33uV      4.673uV    -22.51mV
743ps     -1.105mV   4.673uV    1.785V
946ps     -36.14mV   -97.9uV    2.279V
1.2ns     1.289V     -837.4uV   2.402V
1.497ns   1.753V     -34.47mV   2.457V
1.762ns   1.847V     822.3mV    2.48V
1.921ns   1.878V     1.143V     2.488V
2.703ns   1.941V     1.484V     2.5V
20ns      1.959V     1.548V     2.502V
[Rising Waveform]
R_fixture= 50.000
V_fixture= 3.300
V_fixture_min= 3.140
V_fixture_max= 3.470
|time   V(typ)   V(min)   V(max)
0s        1.278V     1.633V     953.3mV
520ps     1.278V     1.633V     973.7mV
673ps     1.277V     1.633V     2.915V
830ps     1.281V     1.633V     3.319V
1.052ns   2.7V       1.634V     3.396V
1.172ns   3.088V     1.631V     3.417V
1.328ns   3.194V     1.685V     3.435V
1.708ns   3.252V     2.93V      3.457V
2.181ns   3.28V      3.095V     3.466V
20ns      3.3V       3.14V      3.47V
[Falling Waveform]
R_fixture= 50.000
V_fixture= 3.300
V_fixture_min= 3.140
V_fixture_max= 3.470
|time   V(typ)   V(min)   V(max)
0s        3.3V       3.14V      3.47V
564ps     3.299V     3.14V      3.519V
756ps     3.299V     3.14V      1.904V
969ps     3.345V     3.139V     1.256V
1.236ns   2.021V     3.14V      1.059V
1.538ns   1.54V      3.181V     994mV
1.632ns   1.478V     3.157V     983.7mV
2.079ns   1.351V     2.002V     961.5mV
2.864ns   1.294V     1.707V     954mV
20ns      1.278V     1.633V     953.2mV
[Falling Waveform]
R_fixture= 50.000
V_fixture= 0.0
V_fixture_min= 0.0
V_fixture_max= 0.0
|time   V(typ)   V(min)   V(max)
0s        1.959V     1.548V     2.502V
541ps     1.959V     1.548V     2.486V
692ps     1.958V     1.548V     538.1mV
894ps     1.947V     1.548V     113.4mV
1.072ns   670.5mV    1.548V     53.11mV
1.166ns   287.5mV    1.547V     37.74mV
1.479ns   59.16mV    1.529V     14.6mV
1.796ns   24.25mV    318.6mV    4.998mV
2.281ns   8.516mV    39.57mV    1.074mV
20ns      38.52nV    73.76nV    488.4nV
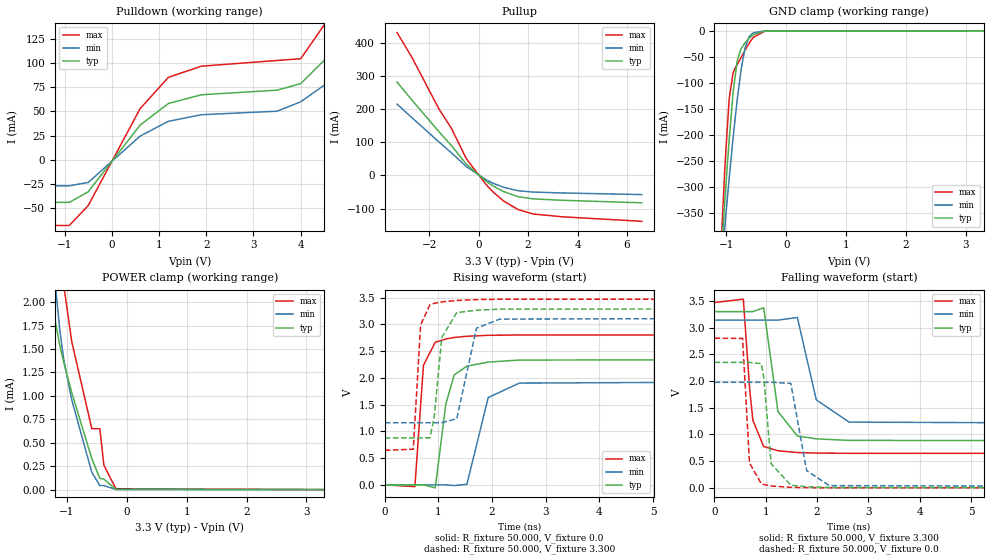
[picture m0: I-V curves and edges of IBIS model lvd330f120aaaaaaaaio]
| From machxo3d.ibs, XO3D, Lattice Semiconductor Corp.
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|   Model lvd330f120aaaaaaaaio
[Model] lvd330f120aaaaaaaaio
Model_type I/O
Polarity   Non-Inverting
Enable   Active-Low
Vinl =  0.800V
Vinh =  2.000V
Vmeas =  1.650V
Cref =  0.0F
Rref =  1.000M
Vref =  0.0V
C_comp   4.200pF   3.800pF   7.500pF
[Temperature Range]   25.000   0.105k   -40.000
[Voltage Range]   3.300V   3.140V   3.470V
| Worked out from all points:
|   slope of the pulldown table from 0 to 0.495 V, typ, clamps not added: 16.2 ohm
|   slope of the pullup table from 0 to 0.495 V, typ, clamps not added: 17.8 ohm
|   GND clamp passes 1 mA (typ) near -0.43 V on its own axis
|   POWER clamp passes 1 mA (typ) near -0.91 V on its own axis
|   rising waveform, R_fixture 50.000, V_fixture 0.0: 20-80 % time 195ps typ, 286ps min, 113ps max; typ from 0 V to 2.35 V
|   rising waveform, R_fixture 50.000, V_fixture 3.300: 20-80 % time 141ps typ, 226ps min, 82ps max; typ from 0.878 V to 3.3 V
|   falling waveform, R_fixture 50.000, V_fixture 3.300: 20-80 % time 217ps typ, 310ps min, 141ps max; typ from 3.3 V to 0.878 V
|   falling waveform, R_fixture 50.000, V_fixture 0.0: 20-80 % time 123ps typ, 187ps min, 84.6ps max; typ from 2.35 V to 0 V
[Pulldown]
|Voltage   I(typ)   I(min)   I(max)
-3.3V     -43.98mA   -26.85mA   -67.81mA
-900mV    -43.98mA   -26.85mA   -67.81mA
-500mV    -33.06mA   -23.42mA   -47.39mA
600mV     35.86mA    24.47mA    52.84mA
1.2V      58.2mA     39.81mA    85.22mA
1.9V      67.18mA    46.57mA    96.69mA
3.5V      71.92mA    50.22mA    102.6mA
4V        78.72mA    59.91mA    104.4mA
5V        127mA      94.43mA    174.7mA
5.3V      146.9mA    108.4mA    207.4mA
5.9V      198.3mA    141.7mA    291.3mA
6.6V      274mA      187.4mA    418.6mA
[Pullup]
|Voltage   I(typ)   I(min)   I(max)
-3.3V     281.3mA    214.9mA    430.6mA
-2.7V     227.3mA    174.1mA    356.2mA
-1.6V     131.2mA    100.4mA    199.6mA
-1.1V     89.83mA    67.72mA    141.9mA
-500mV    34.16mA    26.7mA     50.66mA
300mV     -17.73mA   -13.25mA   -27.57mA
600mV     -32.75mA   -24.32mA   -51.21mA
1V        -48.69mA   -35.83mA   -76.86mA
1.6V      -64.35mA   -46.53mA   -103.4mA
2.2V      -70.98mA   -50.38mA   -116.5mA
3.4V      -75.29mA   -53.18mA   -125.1mA
6.6V      -82.77mA   -58.04mA   -138.6mA
[GND_clamp]
|Voltage   I(typ)   I(min)   I(max)
-3.3V     -4.913A    -3.768A    -6.865A
-1.089V   -436.6mA   -458.9mA   -411.5mA
-1.022V   -318.8mA   -370mA     -253.2mA
-955mV    -210mA     -284.8mA   -131.4mA
-888mV    -117.9mA   -205.1mA   -80.02mA
-821mV    -57.76mA   -133.4mA   -64.74mA
-754mV    -33.88mA   -73.63mA   -51.23mA
-687mV    -22.76mA   -31.63mA   -36.92mA
-620mV    -14.21mA   -11.16mA   -23.73mA
-553mV    -7.411mA   -3.893mA   -12.67mA
-352mV    -131.3uA   -58.9uA    -219uA
3.3V      0A         0A         0A
[POWER_clamp]
|Voltage   I(typ)   I(min)   I(max)
-3.3V     32.67mA    26.87mA    52.85mA
-1.323V   2.804mA    3.246mA    8.665mA
-1.256V   2.134mA    2.67mA     6.124mA
-1.189V   1.77mA     2.147mA    4.184mA
-1.122V   1.54mA     1.71mA     2.893mA
-1.055V   1.357mA    1.39mA     2.18mA
-921mV    1.034mA    956.5uA    1.578mA
-586mV    330uA      184.5uA    649.8uA
-452mV    119.7uA    42.63uA    649.8uA
-385mV    112.2uA    42.63uA    262.6uA
-184mV    2.18uA     1.689uA    8.903uA
3.3V      0A         0A         0A
[Ramp]
| variable   typ   min   max
dV/dt_r   1.409/0.194n   1.186/0.285n   1.681/0.113n
dV/dt_f   1.453/0.217n   1.187/0.315n   1.695/0.141n
R_load = 50.000
[Rising Waveform]
R_fixture= 50.000
V_fixture= 0.0
V_fixture_min= 0.0
V_fixture_max= 0.0
|time   V(typ)   V(min)   V(max)
0s        21.06nV    52.4nV     232.5nV
561ps     -62.55uV   1.028uV    -32.43mV
721ps     -798.4uV   1.028uV    2.235V
940ps     -55.65mV   -64.96uV   2.663V
1.138ns   1.511V     -494.1uV   2.725V
1.294ns   2.055V     -11.54mV   2.754V
1.53ns    2.217V     10.38mV    2.776V
1.928ns   2.294V     1.632V     2.794V
2.509ns   2.332V     1.902V     2.8V
20ns      2.349V     1.976V     2.802V
[Rising Waveform]
R_fixture= 50.000
V_fixture= 3.300
V_fixture_min= 3.140
V_fixture_max= 3.470
|time   V(typ)   V(min)   V(max)
0s        878.1mV    1.161V     645.8mV
531ps     878.1mV    1.161V     666mV
668ps     877.5mV    1.161V     2.988V
841ps     879.4mV    1.161V     3.366V
921ps     1.264V     1.161V     3.39V
1.063ns   2.755V     1.162V     3.418V
1.341ns   3.218V     1.236V     3.445V
1.709ns   3.262V     2.928V     3.461V
2.142ns   3.283V     3.097V     3.467V
20ns      3.3V       3.14V      3.47V
[Falling Waveform]
R_fixture= 50.000
V_fixture= 3.300
V_fixture_min= 3.140
V_fixture_max= 3.470
|time   V(typ)   V(min)   V(max)
0s        3.3V       3.14V      3.47V
562ps     3.299V     3.14V      3.533V
685ps     3.299V     3.14V      1.858V
748ps     3.3V       3.14V      1.265V
959ps     3.371V     3.139V     774.2mV
1.237ns   1.43V      3.14V      694.5mV
1.615ns   971mV      3.19V      661.3mV
1.984ns   917.6mV    1.647V     651.2mV
2.624ns   888.4mV    1.231V     646.5mV
20ns      878mV      1.161V     645.8mV
[Falling Waveform]
R_fixture= 50.000
V_fixture= 0.0
V_fixture_min= 0.0
V_fixture_max= 0.0
|time   V(typ)   V(min)   V(max)
0s        2.349V     1.976V     2.802V
548ps     2.349V     1.976V     2.797V
682ps     2.349V     1.976V     468.5mV
913ps     2.325V     1.976V     75.4mV
959ps     2.076V     1.976V     62.22mV
1.104ns   450.8mV    1.976V     35.2mV
1.488ns   49.44mV    1.956V     9.966mV
1.795ns   20.32mV    323.9mV    4.029mV
2.236ns   7.75mV     42.25mV    1.04mV
20ns      -56.64nV   35.29nV    414nV
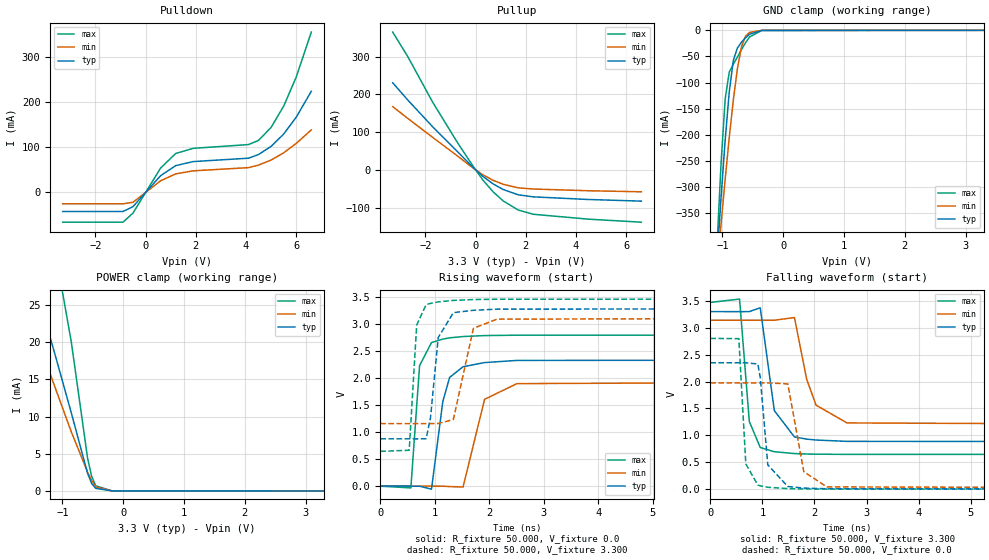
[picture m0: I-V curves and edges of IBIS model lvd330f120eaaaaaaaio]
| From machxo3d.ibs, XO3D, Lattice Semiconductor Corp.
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|   Model lvd330f120eaaaaaaaio
[Model] lvd330f120eaaaaaaaio
Model_type I/O
Polarity   Non-Inverting
Enable   Active-Low
Vinl =  0.800V
Vinh =  2.000V
Vmeas =  1.650V
Cref =  0.0F
Rref =  1.000M
Vref =  0.0V
C_comp   4.200pF   3.800pF   7.500pF
[Temperature Range]   25.000   0.105k   -40.000
[Voltage Range]   3.300V   3.140V   3.470V
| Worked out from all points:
|   slope of the pulldown table from 0 to 0.495 V, typ, clamps not added: 16.2 ohm
|   slope of the pullup table from 0 to 0.495 V, typ, clamps not added: 17.8 ohm
|   GND clamp passes 1 mA (typ) near -0.43 V on its own axis
|   POWER clamp passes 1 mA (typ) near -0.52 V on its own axis
|   rising waveform, R_fixture 50.000, V_fixture 0.0: 20-80 % time 195ps typ, 286ps min, 113ps max; typ from 0 V to 2.35 V
|   rising waveform, R_fixture 50.000, V_fixture 3.300: 20-80 % time 141ps typ, 226ps min, 82ps max; typ from 0.878 V to 3.3 V
|   falling waveform, R_fixture 50.000, V_fixture 3.300: 20-80 % time 217ps typ, 310ps min, 141ps max; typ from 3.3 V to 0.878 V
|   falling waveform, R_fixture 50.000, V_fixture 0.0: 20-80 % time 123ps typ, 187ps min, 84.6ps max; typ from 2.35 V to 0 V
[Pulldown]
|Voltage   I(typ)   I(min)   I(max)
-3.3V     -43.98mA   -26.85mA   -67.81mA
-900mV    -43.98mA   -26.85mA   -67.81mA
-500mV    -33.06mA   -23.42mA   -47.39mA
600mV     35.86mA    24.47mA    52.84mA
1.2V      58.2mA     39.81mA    85.22mA
1.9V      67.18mA    46.57mA    96.69mA
4.1V      74.72mA    53.64mA    105mA
4.5V      82.96mA    59.43mA    114.4mA
5V        101.1mA    70.65mA    143.3mA
5.5V      128.5mA    86.68mA    190.8mA
6V        166mA      107.7mA    255.5mA
6.6V      223.8mA    137.7mA    355.5mA
[Pullup]
|Voltage   I(typ)   I(min)   I(max)
-3.3V     231mA      167.7mA    365.3mA
-2.7V     185.2mA    136.5mA    300.3mA
-1.7V     113.7mA    85.77mA    178.5mA
-700mV    47.12mA    35.9mA     70.15mA
-100mV    6.435mA    4.858mA    9.905mA
300mV     -17.73mA   -13.25mA   -27.57mA
700mV     -37.16mA   -27.54mA   -58.24mA
1.1V      -51.98mA   -38.15mA   -82.25mA
1.7V      -66.04mA   -47.59mA   -106.4mA
2.3V      -71.47mA   -50.68mA   -117.6mA
4.5V      -78.46mA   -55.25mA   -130.6mA
6.6V      -82.77mA   -58.04mA   -138.6mA
[GND_clamp]
|Voltage   I(typ)   I(min)   I(max)
-3.3V     -4.913A    -3.768A    -6.865A
-1.089V   -436.6mA   -458.9mA   -411.5mA
-1.022V   -318.8mA   -370mA     -253.2mA
-955mV    -210mA     -284.8mA   -131.4mA
-888mV    -117.9mA   -205.1mA   -80.02mA
-821mV    -57.76mA   -133.4mA   -64.74mA
-754mV    -33.88mA   -73.63mA   -51.23mA
-687mV    -22.76mA   -31.63mA   -36.92mA
-620mV    -14.21mA   -11.16mA   -23.73mA
-553mV    -7.411mA   -3.893mA   -12.67mA
-352mV    -131.3uA   -58.9uA    -219uA
3.3V      0A         0A         0A
[POWER_clamp]
|Voltage   I(typ)   I(min)   I(max)
-3.3V     82.87mA    74.06mA    118.1mA
-1.926V   41.79mA    34.09mA    64.67mA
-1.725V   35.77mA    28.77mA    56.95mA
-1.658V   33.78mA    27.04mA    54.31mA
-1.189V   20.27mA    15.49mA    35.28mA
-1.122V   18.35mA    13.94mA    32.42mA
-854mV    10.5mA     7.941mA    20.03mA
-586mV    2.349mA    2.531mA    4.384mA
-519mV    997.2uA    1.406mA    1.953mA
-452mV    344.2uA    549.2uA    685.9uA
-184mV    2.187uA    1.695uA    8.906uA
3.3V      0A         0A         0A
[Ramp]
| variable   typ   min   max
dV/dt_r   1.409/0.194n   1.186/0.285n   1.681/0.113n
dV/dt_f   1.453/0.217n   1.187/0.315n   1.695/0.141n
R_load = 50.000
[Rising Waveform]
R_fixture= 50.000
V_fixture= 0.0
V_fixture_min= 0.0
V_fixture_max= 0.0
|time   V(typ)   V(min)   V(max)
0s        21.06nV    52.4nV     232.5nV
561ps     -18.37uV   1.028uV    -32.43mV
721ps     -798.4uV   1.028uV    2.235V
940ps     -55.65mV   -64.96uV   2.663V
1.147ns   1.567V     -494.1uV   2.727V
1.272ns   2.017V     -7.772mV   2.751V
1.519ns   2.215V     -15.14mV   2.775V
1.914ns   2.292V     1.611V     2.793V
2.509ns   2.332V     1.902V     2.8V
20ns      2.349V     1.976V     2.802V
[Rising Waveform]
R_fixture= 50.000
V_fixture= 3.300
V_fixture_min= 3.140
V_fixture_max= 3.470
|time   V(typ)   V(min)   V(max)
0s        878.1mV    1.161V     645.8mV
531ps     878.1mV    1.161V     665.9mV
668ps     877.5mV    1.161V     2.988V
841ps     879.4mV    1.161V     3.366V
921ps     1.264V     1.161V     3.39V
1.063ns   2.755V     1.162V     3.418V
1.341ns   3.218V     1.236V     3.445V
1.709ns   3.262V     2.928V     3.461V
2.142ns   3.283V     3.097V     3.467V
20ns      3.3V       3.14V      3.47V
[Falling Waveform]
R_fixture= 50.000
V_fixture= 3.300
V_fixture_min= 3.140
V_fixture_max= 3.470
|time   V(typ)   V(min)   V(max)
0s        3.3V       3.14V      3.47V
562ps     3.299V     3.14V      3.533V
749ps     3.3V       3.14V      1.258V
959ps     3.371V     3.139V     774.2mV
1.229ns   1.46V      3.139V     695.9mV
1.615ns   971mV      3.19V      661.3mV
1.85ns    930.2mV    2.042V     653.2mV
2.03ns    913.4mV    1.561V     650.2mV
2.624ns   888.4mV    1.231V     646.5mV
20ns      878mV      1.161V     645.8mV
[Falling Waveform]
R_fixture= 50.000
V_fixture= 0.0
V_fixture_min= 0.0
V_fixture_max= 0.0
|time   V(typ)   V(min)   V(max)
0s        2.349V     1.976V     2.802V
548ps     2.349V     1.976V     2.797V
682ps     2.349V     1.976V     468.5mV
913ps     2.325V     1.976V     75.4mV
959ps     2.076V     1.976V     62.22mV
1.104ns   450.8mV    1.976V     35.2mV
1.488ns   49.44mV    1.956V     9.966mV
1.795ns   20.32mV    323.9mV    4.029mV
2.236ns   7.75mV     42.25mV    1.04mV
20ns      -56.64nV   35.29nV    414nV
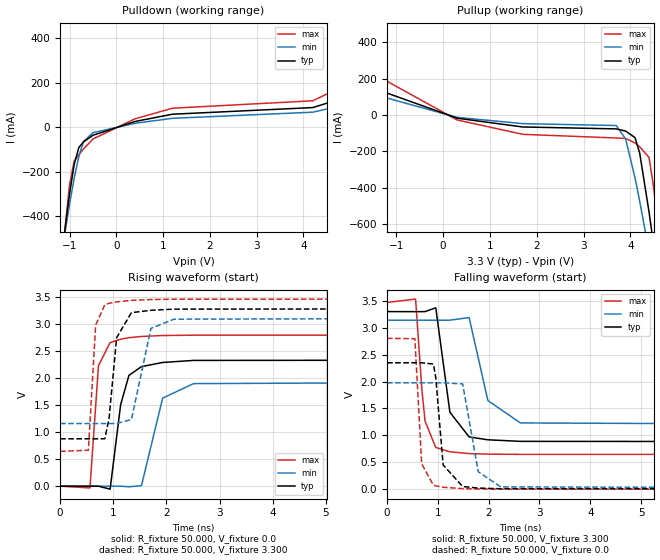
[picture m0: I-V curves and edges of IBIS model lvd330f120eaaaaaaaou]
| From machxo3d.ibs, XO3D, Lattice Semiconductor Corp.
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|   Model lvd330f120eaaaaaaaou
[Model] lvd330f120eaaaaaaaou
Model_type Output
Polarity   Non-Inverting
Enable   Active-High
Vmeas =  1.650V
Cref =  0.0F
Rref =  1.000M
Vref =  0.0V
C_comp   4.200pF   3.800pF   7.500pF
[Temperature Range]   25.000   0.105k   -40.000
[Voltage Range]   3.300V   3.140V   3.470V
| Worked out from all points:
|   slope of the pulldown table from 0 to 0.495 V, typ, clamps not added: 16.2 ohm
|   slope of the pullup table from 0 to 0.495 V, typ, clamps not added: 17.8 ohm
|   rising waveform, R_fixture 50.000, V_fixture 0.0: 20-80 % time 195ps typ, 286ps min, 113ps max; typ from 0 V to 2.35 V
|   rising waveform, R_fixture 50.000, V_fixture 3.300: 20-80 % time 141ps typ, 226ps min, 82ps max; typ from 0.878 V to 3.3 V
|   falling waveform, R_fixture 50.000, V_fixture 3.300: 20-80 % time 217ps typ, 310ps min, 141ps max; typ from 3.3 V to 0.878 V
|   falling waveform, R_fixture 50.000, V_fixture 0.0: 20-80 % time 123ps typ, 187ps min, 84.6ps max; typ from 2.35 V to 0 V
[Pulldown]
|Voltage   I(typ)   I(min)   I(max)
-3.3V     -4.914A    -3.768A    -6.866A
-1.1V     -466.5mA   -478.5mA   -464.3mA
-1V       -301mA     -348.2mA   -261.7mA
-900mV    -168mA     -229.6mA   -152.5mA
-800mV    -91.31mA   -131.6mA   -124.1mA
-700mV    -66.41mA   -64.15mA   -98.36mA
-500mV    -36.65mA   -24.99mA   -53.53mA
400mV     25.4mA     17.33mA    37.45mA
1.2V      58.2mA     39.81mA    85.22mA
4.2V      88.14mA    67.34mA    118.7mA
5.3V      160.3mA    120.1mA    230.6mA
6.6V      306.7mA    216.7mA    467.2mA
[Pullup]
|Voltage   I(typ)   I(min)   I(max)
-3.3V     313.9mA    241.7mA    483.4mA
300mV     -17.73mA   -13.25mA   -27.57mA
1.7V      -66.04mA   -47.59mA   -106.4mA
3.7V      -76.59mA   -58.11mA   -126.6mA
3.9V      -88.69mA   -132.5mA   -129.1mA
4.1V      -124.6mA   -345.5mA   -154.2mA
4.2V      -210.2mA   -474.8mA   -175.2mA
4.4V      -534.7mA   -751.5mA   -233.9mA
4.5V      -720.8mA   -894.9mA   -401.4mA
4.6V      -913mA     -1.04A     -647.5mA
4.7V      -1.109A    -1.187A    -916.8mA
6.6V      -4.996A    -4.072A    -6.497A
[Ramp]
| variable   typ   min   max
dV/dt_r   1.409/0.194n   1.186/0.285n   1.681/0.113n
dV/dt_f   1.453/0.217n   1.187/0.315n   1.695/0.141n
R_load = 50.000
[Rising Waveform]
R_fixture= 50.000
V_fixture= 0.0
V_fixture_min= 0.0
V_fixture_max= 0.0
|time   V(typ)   V(min)   V(max)
0s        21.06nV    52.4nV     232.5nV
561ps     -62.56uV   1.028uV    -32.43mV
721ps     -798.4uV   1.028uV    2.235V
940ps     -55.65mV   -64.94uV   2.663V
1.138ns   1.511V     -494.1uV   2.725V
1.294ns   2.055V     -11.54mV   2.754V
1.53ns    2.217V     10.38mV    2.776V
1.928ns   2.294V     1.632V     2.794V
2.509ns   2.332V     1.902V     2.8V
20ns      2.349V     1.976V     2.802V
[Rising Waveform]
R_fixture= 50.000
V_fixture= 3.300
V_fixture_min= 3.140
V_fixture_max= 3.470
|time   V(typ)   V(min)   V(max)
0s        878.1mV    1.161V     645.8mV
531ps     878.1mV    1.161V     666mV
668ps     877.5mV    1.161V     2.988V
841ps     879.4mV    1.161V     3.366V
921ps     1.264V     1.161V     3.39V
1.063ns   2.755V     1.162V     3.418V
1.341ns   3.218V     1.236V     3.445V
1.709ns   3.262V     2.928V     3.461V
2.142ns   3.283V     3.097V     3.467V
20ns      3.3V       3.14V      3.47V
[Falling Waveform]
R_fixture= 50.000
V_fixture= 3.300
V_fixture_min= 3.140
V_fixture_max= 3.470
|time   V(typ)   V(min)   V(max)
0s        3.3V       3.14V      3.47V
562ps     3.299V     3.14V      3.533V
685ps     3.299V     3.14V      1.858V
748ps     3.3V       3.14V      1.265V
959ps     3.371V     3.139V     774.2mV
1.237ns   1.43V      3.14V      694.5mV
1.615ns   971mV      3.19V      661.3mV
1.984ns   917.6mV    1.647V     651.2mV
2.624ns   888.4mV    1.231V     646.5mV
20ns      878mV      1.161V     645.8mV
[Falling Waveform]
R_fixture= 50.000
V_fixture= 0.0
V_fixture_min= 0.0
V_fixture_max= 0.0
|time   V(typ)   V(min)   V(max)
0s        2.349V     1.976V     2.802V
548ps     2.349V     1.976V     2.797V
682ps     2.349V     1.976V     468.5mV
913ps     2.325V     1.976V     75.4mV
959ps     2.076V     1.976V     62.22mV
1.104ns   450.8mV    1.976V     35.2mV
1.488ns   49.44mV    1.956V     9.966mV
1.795ns   20.32mV    323.9mV    4.029mV
2.236ns   7.75mV     42.25mV    1.04mV
20ns      -56.64nV   35.29nV    414nV
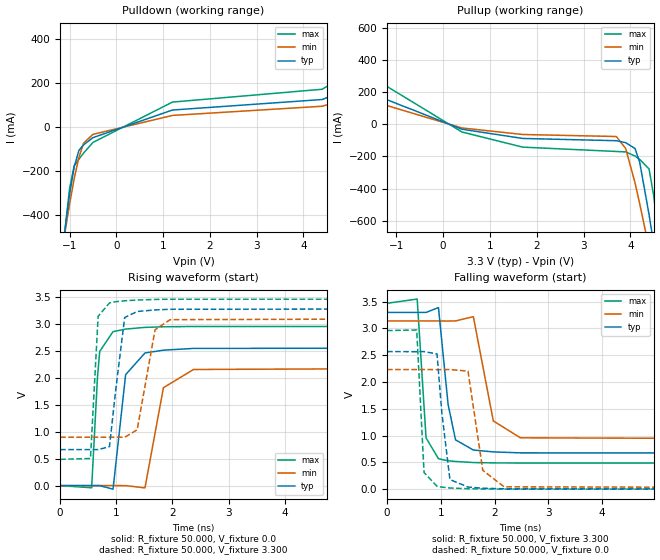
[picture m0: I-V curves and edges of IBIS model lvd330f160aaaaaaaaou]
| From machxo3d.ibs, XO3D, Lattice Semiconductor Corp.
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|   Model lvd330f160aaaaaaaaou
[Model] lvd330f160aaaaaaaaou
Model_type Output
Polarity   Non-Inverting
Enable   Active-High
Vmeas =  1.650V
Cref =  0.0F
Rref =  1.000M
Vref =  0.0V
C_comp   4.200pF   3.800pF   7.500pF
[Temperature Range]   25.000   0.105k   -40.000
[Voltage Range]   3.300V   3.140V   3.470V
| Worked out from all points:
|   slope of the pulldown table from 0 to 0.495 V, typ, clamps not added: 12.2 ohm
|   slope of the pullup table from 0 to 0.495 V, typ, clamps not added: 13.4 ohm
|   rising waveform, R_fixture 50.000, V_fixture 0.0: 20-80 % time 148ps typ, 222ps min, 85.5ps max; typ from 0 V to 2.57 V
|   rising waveform, R_fixture 50.000, V_fixture 3.300: 20-80 % time 121ps typ, 204ps min, 68.3ps max; typ from 0.669 V to 3.3 V
|   falling waveform, R_fixture 50.000, V_fixture 3.300: 20-80 % time 159ps typ, 244ps min, 102ps max; typ from 3.3 V to 0.669 V
|   falling waveform, R_fixture 50.000, V_fixture 0.0: 20-80 % time 105ps typ, 164ps min, 69.8ps max; typ from 2.57 V to 0 V
[Pulldown]
|Voltage   I(typ)   I(min)   I(max)
-3.3V     -4.914A    -3.769A    -6.866A
-1.1V     -469.8mA   -480.1mA   -472.7mA
-1V       -307.4mA   -350.5mA   -279.8mA
-900mV    -179.8mA   -233.2mA   -175.1mA
-800mV    -106mA     -137.7mA   -145.2mA
-700mV    -80.34mA   -72.85mA   -117.9mA
-500mV    -47.66mA   -32.8mA    -69.33mA
1.2V      77.59mA    53.08mA    113.6mA
4.4V      125.2mA    94.73mA    171.7mA
5.3V      200.8mA    149.5mA    288.2mA
6.1V      305.7mA    220.1mA    456.9mA
6.6V      388.5mA    272.8mA    592.1mA
[Pullup]
|Voltage   I(typ)   I(min)   I(max)
-3.3V     392.1mA    298mA      605.2mA
400mV     -30.71mA   -22.9mA    -47.84mA
1.7V      -88.05mA   -63.45mA   -141.9mA
3.7V      -102mA     -76.03mA   -168.8mA
3.9V      -114.3mA   -150.6mA   -171.6mA
4.1V      -150.4mA   -363.7mA   -197mA
4.2V      -236.1mA   -493mA     -218.2mA
4.4V      -560.7mA   -769.8mA   -277.2mA
4.5V      -747mA     -913.3mA   -444.9mA
4.6V      -939.2mA   -1.059A    -691.2mA
4.7V      -1.135A    -1.206A    -960.6mA
6.6V      -5.024A    -4.091A    -6.543A
[Ramp]
| variable   typ   min   max
dV/dt_r   1.541/0.148n   1.340/0.222n   1.777/85.244p
dV/dt_f   1.578/0.158n   1.344/0.241n   1.790/0.102n
R_load = 50.000
[Rising Waveform]
R_fixture= 50.000
V_fixture= 0.0
V_fixture_min= 0.0
V_fixture_max= 0.0
|time   V(typ)   V(min)   V(max)
0s        16.71nV    42.4nV     181.6nV
561ps     -21.77uV   -266.7nV   -40.84mV
665ps     -514.9uV   -266.7nV   2.016V
705ps     -756.4uV   -266.7nV   2.497V
942ps     -66.74mV   -63.41uV   2.863V
1.167ns   2.064V     -539.6uV   2.912V
1.511ns   2.467V     -42.78mV   2.943V
1.84ns    2.519V     1.821V     2.954V
2.376ns   2.552V     2.16V      2.96V
20ns      2.568V     2.233V     2.961V
[Rising Waveform]
R_fixture= 50.000
V_fixture= 3.300
V_fixture_min= 3.140
V_fixture_max= 3.470
|time   V(typ)   V(min)   V(max)
0s        669.4mV    899.2mV    487.7mV
540ps     669.4mV    899.2mV    504.2mV
677ps     668.8mV    899.2mV    3.15V
879ps     724.9mV    899.2mV    3.398V
987ps     1.752V     898.8mV    3.42V
1.149ns   3.126V     898.6mV    3.438V
1.372ns   3.239V     1.037V     3.452V
1.691ns   3.268V     2.899V     3.463V
1.96ns    3.28V      3.087V     3.467V
20ns      3.3V       3.14V      3.47V
[Falling Waveform]
R_fixture= 50.000
V_fixture= 3.300
V_fixture_min= 3.140
V_fixture_max= 3.470
|time   V(typ)   V(min)   V(max)
0s        3.3V       3.14V      3.47V
561ps     3.299V     3.14V      3.549V
726ps     3.3V       3.14V      957mV
957ps     3.389V     3.14V      567.9mV
1.136ns   1.583V     3.139V     530.3mV
1.274ns   921.4mV    3.141V     517.2mV
1.606ns   730.8mV    3.22V      497.1mV
1.977ns   695.7mV    1.274V     490.8mV
2.481ns   677.7mV    958.8mV    488mV
20ns      669.4mV    899.2mV    487.4mV
[Falling Waveform]
R_fixture= 50.000
V_fixture= 0.0
V_fixture_min= 0.0
V_fixture_max= 0.0
|time   V(typ)   V(min)   V(max)
0s        2.568V     2.233V     2.961V
552ps     2.567V     2.233V     2.972V
689ps     2.568V     2.233V     310.1mV
930ps     2.524V     2.232V     53.57mV
1.02ns    1.422V     2.232V     38.55mV
1.17ns    180.3mV    2.233V     21.58mV
1.506ns   39.05mV    2.204V     7.768mV
1.782ns   17.23mV    351.2mV    3.062mV
2.177ns   7.084mV    44.02mV    967.9uV
20ns      -106.8nV   3.043nV    236.3nV
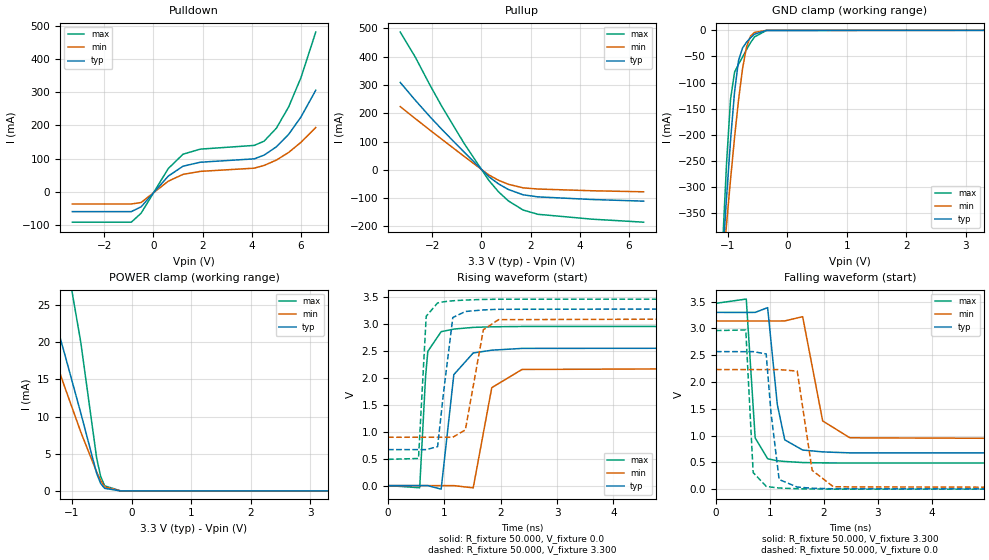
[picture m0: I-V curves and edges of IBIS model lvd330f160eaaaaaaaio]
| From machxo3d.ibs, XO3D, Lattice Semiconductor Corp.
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|   Model lvd330f160eaaaaaaaio
[Model] lvd330f160eaaaaaaaio
Model_type I/O
Polarity   Non-Inverting
Enable   Active-Low
Vinl =  0.800V
Vinh =  2.000V
Vmeas =  1.650V
Cref =  0.0F
Rref =  1.000M
Vref =  0.0V
C_comp   4.200pF   3.800pF   7.500pF
[Temperature Range]   25.000   0.105k   -40.000
[Voltage Range]   3.300V   3.140V   3.470V
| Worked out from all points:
|   slope of the pulldown table from 0 to 0.495 V, typ, clamps not added: 12.2 ohm
|   slope of the pullup table from 0 to 0.495 V, typ, clamps not added: 13.4 ohm
|   GND clamp passes 1 mA (typ) near -0.43 V on its own axis
|   POWER clamp passes 1 mA (typ) near -0.52 V on its own axis
|   rising waveform, R_fixture 50.000, V_fixture 0.0: 20-80 % time 148ps typ, 222ps min, 85.5ps max; typ from 0 V to 2.57 V
|   rising waveform, R_fixture 50.000, V_fixture 3.300: 20-80 % time 121ps typ, 204ps min, 68.3ps max; typ from 0.669 V to 3.3 V
|   falling waveform, R_fixture 50.000, V_fixture 3.300: 20-80 % time 159ps typ, 244ps min, 102ps max; typ from 3.3 V to 0.669 V
|   falling waveform, R_fixture 50.000, V_fixture 0.0: 20-80 % time 105ps typ, 164ps min, 69.8ps max; typ from 2.57 V to 0 V
[Pulldown]
|Voltage   I(typ)   I(min)   I(max)
-3.3V     -58.64mA   -35.81mA   -90.41mA
-900mV    -58.64mA   -35.81mA   -90.41mA
-500mV    -44.08mA   -31.23mA   -63.19mA
600mV     47.81mA    32.63mA    70.46mA
1.2V      77.59mA    53.08mA    113.6mA
1.9V      89.57mA    62.1mA     128.9mA
4.1V      99.73mA    71.79mA    140.1mA
4.5V      111mA      80mA       152.9mA
5V        135.9mA    96.04mA    191.9mA
5.5V      173.5mA    119.1mA    255.9mA
6V        225.5mA    149.5mA    343.8mA
6.6V      305.7mA    193.7mA    480.3mA
[Pullup]
|Voltage   I(typ)   I(min)   I(max)
-3.3V     309.2mA    223.9mA    487.2mA
-2.7V     247.5mA    182.2mA    400.8mA
-2.1V     188.9mA    141.3mA    301.2mA
-1.6V     142.5mA    107.7mA    223.1mA
-700mV    62.84mA    47.87mA    93.53mA
300mV     -23.64mA   -17.66mA   -36.76mA
700mV     -49.55mA   -36.72mA   -77.66mA
1.1V      -69.31mA   -50.87mA   -109.7mA
1.7V      -88.05mA   -63.45mA   -141.9mA
2.3V      -95.3mA    -67.57mA   -156.9mA
4.5V      -104.6mA   -73.67mA   -174.1mA
6.6V      -110.4mA   -77.39mA   -184.8mA
[GND_clamp]
|Voltage   I(typ)   I(min)   I(max)
-3.3V     -4.913A    -3.768A    -6.865A
-1.089V   -436.6mA   -458.9mA   -411.5mA
-1.022V   -318.8mA   -370mA     -253.2mA
-955mV    -210mA     -284.8mA   -131.4mA
-888mV    -117.9mA   -205.1mA   -80.02mA
-821mV    -57.76mA   -133.4mA   -64.74mA
-754mV    -33.88mA   -73.63mA   -51.23mA
-687mV    -22.76mA   -31.63mA   -36.92mA
-620mV    -14.21mA   -11.16mA   -23.73mA
-553mV    -7.411mA   -3.893mA   -12.67mA
-352mV    -131.3uA   -58.9uA    -219uA
3.3V      0A         0A         0A
[POWER_clamp]
|Voltage   I(typ)   I(min)   I(max)
-3.3V     82.87mA    74.06mA    118.1mA
-1.926V   41.79mA    34.09mA    64.67mA
-1.725V   35.77mA    28.77mA    56.95mA
-1.658V   33.78mA    27.04mA    54.31mA
-1.189V   20.27mA    15.49mA    35.28mA
-1.122V   18.35mA    13.94mA    32.42mA
-854mV    10.5mA     7.941mA    20.03mA
-586mV    2.349mA    2.531mA    4.384mA
-519mV    997.2uA    1.406mA    1.953mA
-452mV    344.2uA    549.2uA    685.9uA
-184mV    2.187uA    1.695uA    8.906uA
3.3V      0A         0A         0A
[Ramp]
| variable   typ   min   max
dV/dt_r   1.541/0.148n   1.340/0.222n   1.777/85.244p
dV/dt_f   1.578/0.158n   1.344/0.241n   1.790/0.102n
R_load = 50.000
[Rising Waveform]
R_fixture= 50.000
V_fixture= 0.0
V_fixture_min= 0.0
V_fixture_max= 0.0
|time   V(typ)   V(min)   V(max)
0s        16.71nV    42.4nV     181.6nV
561ps     -21.78uV   -267.8nV   -40.84mV
665ps     -514.9uV   -267.8nV   2.016V
705ps     -756.4uV   -267.8nV   2.497V
942ps     -66.74mV   -63.43uV   2.863V
1.167ns   2.064V     -539.6uV   2.912V
1.511ns   2.467V     -42.78mV   2.943V
1.84ns    2.519V     1.821V     2.954V
2.376ns   2.552V     2.16V      2.96V
20ns      2.568V     2.233V     2.961V
[Rising Waveform]
R_fixture= 50.000
V_fixture= 3.300
V_fixture_min= 3.140
V_fixture_max= 3.470
|time   V(typ)   V(min)   V(max)
0s        669.4mV    899.2mV    487.7mV
540ps     669.4mV    899.2mV    504.2mV
677ps     668.8mV    899.2mV    3.15V
879ps     724.9mV    899.2mV    3.398V
987ps     1.752V     898.8mV    3.42V
1.149ns   3.126V     898.6mV    3.438V
1.372ns   3.239V     1.037V     3.452V
1.691ns   3.268V     2.899V     3.463V
1.96ns    3.28V      3.087V     3.467V
20ns      3.3V       3.14V      3.47V
[Falling Waveform]
R_fixture= 50.000
V_fixture= 3.300
V_fixture_min= 3.140
V_fixture_max= 3.470
|time   V(typ)   V(min)   V(max)
0s        3.3V       3.14V      3.47V
561ps     3.299V     3.14V      3.549V
726ps     3.3V       3.14V      957mV
957ps     3.389V     3.14V      567.9mV
1.136ns   1.583V     3.139V     530.3mV
1.274ns   921.4mV    3.141V     517.2mV
1.606ns   730.8mV    3.22V      497.1mV
1.977ns   695.7mV    1.274V     490.6mV
2.481ns   677.7mV    958.8mV    488.1mV
20ns      669.4mV    899.2mV    487.4mV
[Falling Waveform]
R_fixture= 50.000
V_fixture= 0.0
V_fixture_min= 0.0
V_fixture_max= 0.0
|time   V(typ)   V(min)   V(max)
0s        2.568V     2.233V     2.961V
552ps     2.567V     2.233V     2.972V
689ps     2.568V     2.233V     310.1mV
930ps     2.524V     2.232V     53.57mV
1.02ns    1.422V     2.232V     38.55mV
1.17ns    180.3mV    2.233V     21.58mV
1.506ns   39.05mV    2.204V     7.768mV
1.782ns   17.23mV    351.2mV    3.062mV
2.177ns   7.084mV    44.02mV    971.1uV
20ns      -106.8nV   3.043nV    236.3nV
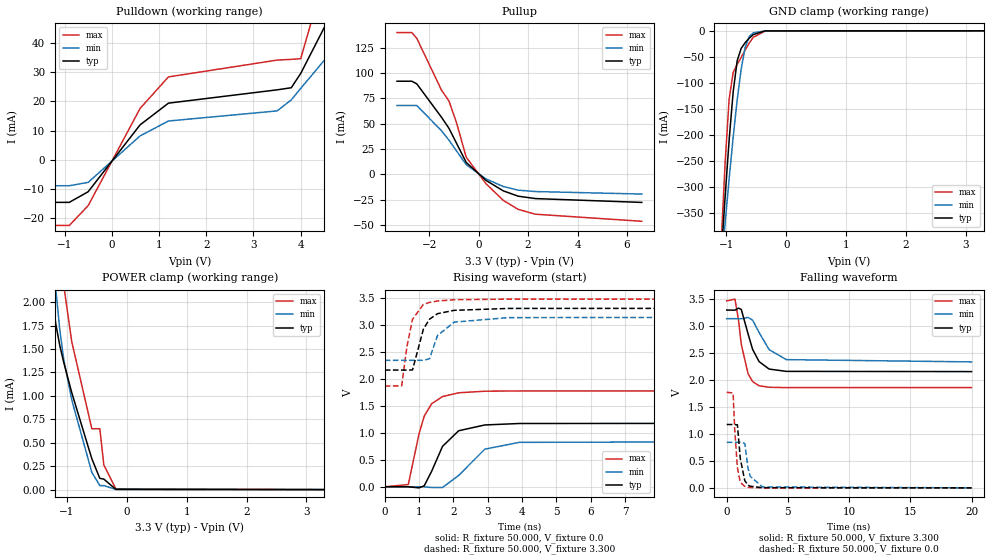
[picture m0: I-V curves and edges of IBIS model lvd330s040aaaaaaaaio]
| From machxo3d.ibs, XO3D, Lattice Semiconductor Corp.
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|   Model lvd330s040aaaaaaaaio
[Model] lvd330s040aaaaaaaaio
Model_type I/O
Polarity   Non-Inverting
Enable   Active-Low
Vinl =  0.800V
Vinh =  2.000V
Vmeas =  1.650V
Cref =  0.0F
Rref =  1.000M
Vref =  0.0V
C_comp   4.200pF   3.800pF   7.500pF
[Temperature Range]   25.000   0.105k   -40.000
[Voltage Range]   3.300V   3.140V   3.470V
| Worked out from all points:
|   slope of the pulldown table from 0 to 0.495 V, typ, clamps not added: 48.6 ohm
|   slope of the pullup table from 0 to 0.495 V, typ, clamps not added: 53.4 ohm
|   GND clamp passes 1 mA (typ) near -0.43 V on its own axis
|   POWER clamp passes 1 mA (typ) near -0.91 V on its own axis
|   rising waveform, R_fixture 50.000, V_fixture 0.0: 20-80 % time 587ps typ, 760ps min, 421ps max; typ from 0 V to 1.18 V
|   rising waveform, R_fixture 50.000, V_fixture 3.300: 20-80 % time 369ps typ, 445ps min, 275ps max; typ from 2.16 V to 3.3 V
|   falling waveform, R_fixture 50.000, V_fixture 3.300: 20-80 % time 996ps typ, 1.36ns min, 728ps max; typ from 3.3 V to 2.16 V
|   falling waveform, R_fixture 50.000, V_fixture 0.0: 20-80 % time 379ps typ, 443ps min, 295ps max; typ from 1.18 V to 0 V
[Pulldown]
|Voltage   I(typ)   I(min)   I(max)
-3.3V     -14.66mA   -8.951mA   -22.6mA
-900mV    -14.66mA   -8.951mA   -22.6mA
-500mV    -11.02mA   -7.807mA   -15.8mA
600mV     11.95mA    8.157mA    17.61mA
1.2V      19.4mA     13.27mA    28.41mA
3.5V      23.97mA    16.74mA    34.18mA
3.8V      24.69mA    20.53mA    34.43mA
4V        29.6mA     24.46mA    34.67mA
4.6V      48.59mA    36.07mA    68.51mA
5V        57.53mA    43.63mA    77.58mA
5.5V      72.19mA    53.88mA    102.2mA
6.6V      110.1mA    75.08mA    168.6mA
[Pullup]
|Voltage   I(typ)   I(min)   I(max)
-3.3V     91.85mA    67.9mA     139.8mA
-2.7V     91.85mA    67.9mA     139.8mA
-2.5V     89.23mA    67.9mA     134.1mA
-1.5V     56.3mA     43.03mA    82.99mA
-1.2V     45.46mA    33.76mA    72.46mA
-900mV    31.01mA    23.36mA    51.39mA
-500mV    11.76mA    9.598mA    16.89mA
300mV     -5.911mA   -4.415mA   -9.19mA
1V        -16.23mA   -11.94mA   -25.62mA
1.6V      -21.45mA   -15.51mA   -34.45mA
2.3V      -23.82mA   -16.89mA   -39.22mA
6.6V      -27.59mA   -19.35mA   -46.2mA
[GND_clamp]
|Voltage   I(typ)   I(min)   I(max)
-3.3V     -4.913A    -3.768A    -6.865A
-1.089V   -436.6mA   -458.9mA   -411.5mA
-1.022V   -318.8mA   -370mA     -253.2mA
-955mV    -210mA     -284.8mA   -131.4mA
-888mV    -117.9mA   -205.1mA   -80.02mA
-821mV    -57.76mA   -133.4mA   -64.74mA
-754mV    -33.88mA   -73.63mA   -51.23mA
-687mV    -22.76mA   -31.63mA   -36.92mA
-620mV    -14.21mA   -11.16mA   -23.73mA
-553mV    -7.411mA   -3.893mA   -12.67mA
-352mV    -131.3uA   -58.9uA    -219uA
3.3V      0A         0A         0A
[POWER_clamp]
|Voltage   I(typ)   I(min)   I(max)
-3.3V     32.67mA    26.87mA    52.85mA
-1.323V   2.804mA    3.246mA    8.665mA
-1.256V   2.134mA    2.67mA     6.124mA
-1.189V   1.77mA     2.147mA    4.184mA
-1.122V   1.54mA     1.71mA     2.893mA
-1.055V   1.357mA    1.39mA     2.18mA
-921mV    1.034mA    956.5uA    1.578mA
-586mV    330uA      184.5uA    649.8uA
-452mV    119.7uA    42.63uA    649.8uA
-385mV    112.2uA    42.63uA    262.6uA
-184mV    2.18uA     1.689uA    8.903uA
3.3V      0A         0A         0A
[Ramp]
| variable   typ   min   max
dV/dt_r   0.705/0.588n   0.507/0.758n   1.064/0.421n
dV/dt_f   0.685/1.008n   0.481/1.355n   0.965/0.726n
R_load = 50.000
[Rising Waveform]
R_fixture= 50.000
V_fixture= 0.0
V_fixture_min= 0.0
V_fixture_max= 0.0
|time   V(typ)   V(min)   V(max)
0s        43.91nV    99.25nV    528.4nV
685ps     -820.6uV   7.984uV    40.69mV
996ps     -20.28mV   -186.7uV   975.7mV
1.15ns    19.05mV    -447.5uV   1.309V
1.367ns   289.6mV    -13.97mV   1.537V
1.681ns   746.8mV    -13.81mV   1.668V
2.152ns   1.036V     209.6mV    1.738V
2.914ns   1.143V     696.1mV    1.767V
3.921ns   1.17V      821.5mV    1.772V
20ns      1.176V     844.4mV    1.773V
[Rising Waveform]
R_fixture= 50.000
V_fixture= 3.300
V_fixture_min= 3.140
V_fixture_max= 3.470
|time   V(typ)   V(min)   V(max)
0s        2.158V     2.338V     1.861V
492ps     2.158V     2.338V     1.868V
643ps     2.157V     2.338V     2.586V
808ps     2.161V     2.338V     3.097V
1.124ns   2.914V     2.338V     3.372V
1.301ns   3.098V     2.367V     3.409V
1.536ns   3.201V     2.797V     3.436V
2.023ns   3.263V     3.045V     3.459V
3.604ns   3.298V     3.128V     3.47V
20ns      3.3V       3.14V      3.47V
[Falling Waveform]
R_fixture= 50.000
V_fixture= 3.300
V_fixture_min= 3.140
V_fixture_max= 3.470
|time   V(typ)   V(min)   V(max)
0s        3.3V       3.14V      3.47V
671ps     3.298V     3.14V      3.503V
959ps     3.336V     3.139V     3.119V
1.189ns   3.312V     3.138V     2.664V
1.744ns   2.857V     3.164V     2.117V
2.116ns   2.57V      3.111V     1.972V
2.642ns   2.344V     2.884V     1.895V
3.461ns   2.205V     2.567V     1.867V
4.872ns   2.162V     2.38V      1.861V
20ns      2.158V     2.338V     1.861V
[Falling Waveform]
R_fixture= 50.000
V_fixture= 0.0
V_fixture_min= 0.0
V_fixture_max= 0.0
|time   V(typ)   V(min)   V(max)
0s        1.176V     844.4mV    1.773V
519ps     1.175V     844.4mV    1.762V
651ps     1.175V     844.5mV    1.086V
872ps     1.17V      844.2mV    374.2mV
1.111ns   539.4mV    843.6mV    101.5mV
1.475ns   133.7mV    825.9mV    26.79mV
1.737ns   51.85mV    366.8mV    11.72mV
1.919ns   30.59mV    214.3mV    6.477mV
2.924ns   2.939mV    16.91mV    382.9uV
20ns      67.95nV    166.9nV    608.1nV
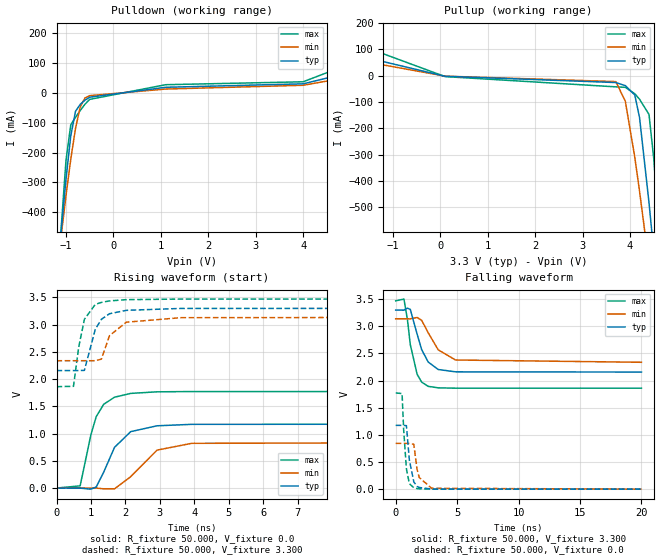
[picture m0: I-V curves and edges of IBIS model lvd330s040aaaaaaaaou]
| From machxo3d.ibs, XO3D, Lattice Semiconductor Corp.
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|   Model lvd330s040aaaaaaaaou
[Model] lvd330s040aaaaaaaaou
Model_type Output
Polarity   Non-Inverting
Enable   Active-High
Vmeas =  1.650V
Cref =  0.0F
Rref =  1.000M
Vref =  0.0V
C_comp   4.200pF   3.800pF   7.500pF
[Temperature Range]   25.000   0.105k   -40.000
[Voltage Range]   3.300V   3.140V   3.470V
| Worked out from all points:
|   slope of the pulldown table from 0 to 0.495 V, typ, clamps not added: 48.6 ohm
|   slope of the pullup table from 0 to 0.495 V, typ, clamps not added: 53.4 ohm
|   rising waveform, R_fixture 50.000, V_fixture 0.0: 20-80 % time 587ps typ, 760ps min, 421ps max; typ from 0 V to 1.18 V
|   rising waveform, R_fixture 50.000, V_fixture 3.300: 20-80 % time 369ps typ, 445ps min, 275ps max; typ from 2.16 V to 3.3 V
|   falling waveform, R_fixture 50.000, V_fixture 3.300: 20-80 % time 996ps typ, 1.36ns min, 728ps max; typ from 3.3 V to 2.16 V
|   falling waveform, R_fixture 50.000, V_fixture 0.0: 20-80 % time 379ps typ, 443ps min, 295ps max; typ from 1.18 V to 0 V
[Pulldown]
|Voltage   I(typ)   I(min)   I(max)
-3.3V     -4.914A    -3.768A    -6.865A
-1.1V     -459.8mA   -475.4mA   -447.6mA
-1V       -288.2mA   -343.8mA   -225.5mA
-900mV    -144.4mA   -222.4mA   -107.3mA
-800mV    -62mA      -119.3mA   -81.84mA
-700mV    -38.56mA   -46.76mA   -59.22mA
-600mV    -24.6mA    -17.1mA    -38.05mA
-500mV    -14.61mA   -9.377mA   -21.94mA
1.1V      18.49mA    12.63mA    27.15mA
4V        30.15mA    25.25mA    36.93mA
5.4V      83.79mA    64.65mA    122.1mA
6.6V      142.8mA    104.4mA    217.2mA
[Pullup]
|Voltage   I(typ)   I(min)   I(max)
-3.3V     114.8mA    83.62mA    179.2mA
-2.5V     109.3mA    83.62mA    169.8mA
100mV     -2.073mA   -1.554mA   -3.21mA
3.7V      -25.83mA   -22.27mA   -42.22mA
3.9V      -37.55mA   -96.42mA   -44mA
4.1V      -73.11mA   -309.2mA   -68.45mA
4.2V      -158.5mA   -438.3mA   -89.1mA
4.4V      -482.5mA   -714.8mA   -147.1mA
4.5V      -668.5mA   -858mA     -314.3mA
4.6V      -860.5mA   -1.003A    -560.2mA
4.7V      -1.056A    -1.15A     -829.1mA
6.6V      -4.941A    -4.033A    -6.405A
[Ramp]
| variable   typ   min   max
dV/dt_r   0.705/0.588n   0.507/0.758n   1.064/0.421n
dV/dt_f   0.685/1.008n   0.481/1.355n   0.965/0.726n
R_load = 50.000
[Rising Waveform]
R_fixture= 50.000
V_fixture= 0.0
V_fixture_min= 0.0
V_fixture_max= 0.0
|time   V(typ)   V(min)   V(max)
0s        43.91nV    99.25nV    528.4nV
685ps     -820.5uV   7.984uV    40.69mV
996ps     -20.28mV   -186.7uV   975.7mV
1.15ns    19.05mV    -447.5uV   1.309V
1.367ns   289.6mV    -13.97mV   1.537V
1.681ns   746.8mV    -13.81mV   1.668V
2.152ns   1.036V     209.6mV    1.738V
2.914ns   1.143V     696.1mV    1.767V
3.921ns   1.17V      821.5mV    1.772V
20ns      1.176V     844.4mV    1.773V
[Rising Waveform]
R_fixture= 50.000
V_fixture= 3.300
V_fixture_min= 3.140
V_fixture_max= 3.470
|time   V(typ)   V(min)   V(max)
0s        2.158V     2.338V     1.861V
492ps     2.158V     2.338V     1.868V
643ps     2.157V     2.338V     2.586V
808ps     2.161V     2.338V     3.097V
1.124ns   2.914V     2.338V     3.372V
1.301ns   3.098V     2.367V     3.409V
1.536ns   3.201V     2.797V     3.436V
2.023ns   3.263V     3.045V     3.459V
3.604ns   3.298V     3.128V     3.47V
20ns      3.3V       3.14V      3.47V
[Falling Waveform]
R_fixture= 50.000
V_fixture= 3.300
V_fixture_min= 3.140
V_fixture_max= 3.470
|time   V(typ)   V(min)   V(max)
0s        3.3V       3.14V      3.47V
671ps     3.298V     3.14V      3.503V
959ps     3.336V     3.139V     3.119V
1.189ns   3.312V     3.138V     2.664V
1.744ns   2.857V     3.164V     2.117V
2.116ns   2.57V      3.111V     1.972V
2.642ns   2.344V     2.884V     1.895V
3.461ns   2.205V     2.567V     1.867V
4.871ns   2.162V     2.38V      1.861V
20ns      2.158V     2.338V     1.861V
[Falling Waveform]
R_fixture= 50.000
V_fixture= 0.0
V_fixture_min= 0.0
V_fixture_max= 0.0
|time   V(typ)   V(min)   V(max)
0s        1.176V     844.4mV    1.773V
519ps     1.175V     844.4mV    1.762V
651ps     1.175V     844.5mV    1.086V
872ps     1.17V      844.2mV    374.2mV
1.111ns   539.4mV    843.6mV    101.5mV
1.475ns   133.7mV    825.9mV    26.79mV
1.737ns   51.85mV    366.8mV    11.72mV
1.919ns   30.59mV    214.3mV    6.477mV
2.924ns   2.939mV    16.91mV    382.9uV
20ns      67.95nV    166.9nV    608.1nV
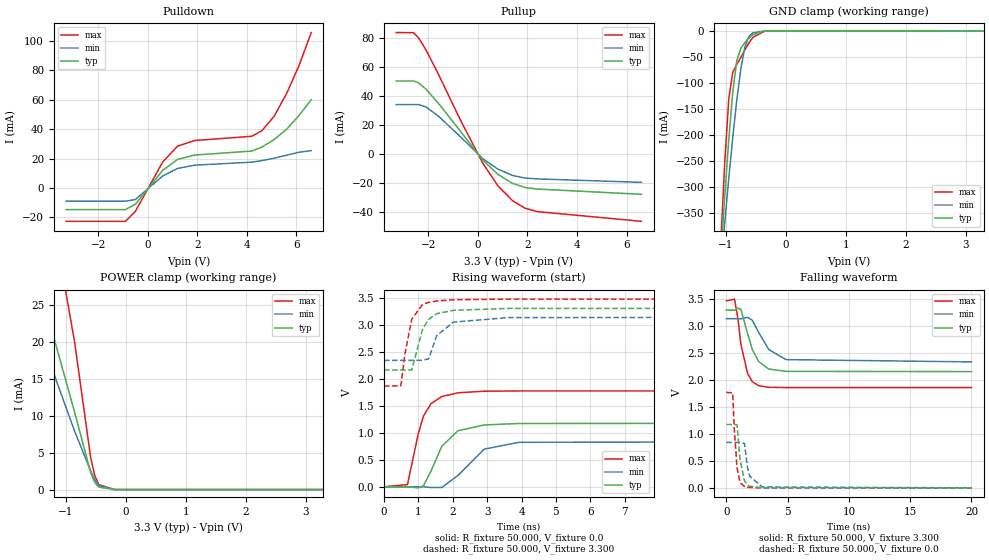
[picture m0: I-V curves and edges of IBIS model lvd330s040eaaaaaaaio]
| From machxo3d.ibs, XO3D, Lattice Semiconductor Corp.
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|   Model lvd330s040eaaaaaaaio
[Model] lvd330s040eaaaaaaaio
Model_type I/O
Polarity   Non-Inverting
Enable   Active-Low
Vinl =  0.800V
Vinh =  2.000V
Vmeas =  1.650V
Cref =  0.0F
Rref =  1.000M
Vref =  0.0V
C_comp   4.200pF   3.800pF   7.500pF
[Temperature Range]   25.000   0.105k   -40.000
[Voltage Range]   3.300V   3.140V   3.470V
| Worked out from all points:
|   slope of the pulldown table from 0 to 0.495 V, typ, clamps not added: 48.6 ohm
|   slope of the pullup table from 0 to 0.495 V, typ, clamps not added: 53.4 ohm
|   GND clamp passes 1 mA (typ) near -0.43 V on its own axis
|   POWER clamp passes 1 mA (typ) near -0.52 V on its own axis
|   rising waveform, R_fixture 50.000, V_fixture 0.0: 20-80 % time 587ps typ, 760ps min, 421ps max; typ from 0 V to 1.18 V
|   rising waveform, R_fixture 50.000, V_fixture 3.300: 20-80 % time 369ps typ, 445ps min, 275ps max; typ from 2.16 V to 3.3 V
|   falling waveform, R_fixture 50.000, V_fixture 3.300: 20-80 % time 996ps typ, 1.36ns min, 728ps max; typ from 3.3 V to 2.16 V
|   falling waveform, R_fixture 50.000, V_fixture 0.0: 20-80 % time 379ps typ, 443ps min, 295ps max; typ from 1.18 V to 0 V
[Pulldown]
|Voltage   I(typ)   I(min)   I(max)
-3.3V     -14.66mA   -8.951mA   -22.6mA
-900mV    -14.66mA   -8.951mA   -22.6mA
-500mV    -11.02mA   -7.807mA   -15.8mA
600mV     11.95mA    8.157mA    17.61mA
1.2V      19.4mA     13.27mA    28.41mA
1.9V      22.39mA    15.52mA    32.23mA
4.2V      25.08mA    17.53mA    35.11mA
4.6V      27.7mA     18.56mA    38.76mA
5.1V      32.84mA    20.22mA    48.65mA
5.6V      39.83mA    22.24mA    63.92mA
6.1V      49.03mA    24.26mA    82.76mA
6.6V      59.9mA     25.37mA    105.5mA
[Pullup]
|Voltage   I(typ)   I(min)   I(max)
-3.3V     50.56mA    34.27mA    83.9mA
-2.6V     50.56mA    34.27mA    83.8mA
-2.4V     49.31mA    34.27mA    80.36mA
-2.1V     44.91mA    32.65mA    72.07mA
-1.6V     35.25mA    26.38mA    55.33mA
-700mV    15.71mA    11.97mA    23.38mA
200mV     -4.043mA   -3.026mA   -6.275mA
800mV     -13.76mA   -10.18mA   -21.62mA
1.4V      -20.07mA   -14.6mA    -32.02mA
1.9V      -22.89mA   -16.38mA   -37.17mA
2.4V      -23.97mA   -16.98mA   -39.52mA
6.6V      -27.59mA   -19.35mA   -46.2mA
[GND_clamp]
|Voltage   I(typ)   I(min)   I(max)
-3.3V     -4.913A    -3.768A    -6.865A
-1.089V   -436.6mA   -458.9mA   -411.5mA
-1.022V   -318.8mA   -370mA     -253.2mA
-955mV    -210mA     -284.8mA   -131.4mA
-888mV    -117.9mA   -205.1mA   -80.02mA
-821mV    -57.76mA   -133.4mA   -64.74mA
-754mV    -33.88mA   -73.63mA   -51.23mA
-687mV    -22.76mA   -31.63mA   -36.92mA
-620mV    -14.21mA   -11.16mA   -23.73mA
-553mV    -7.411mA   -3.893mA   -12.67mA
-352mV    -131.3uA   -58.9uA    -219uA
3.3V      0A         0A         0A
[POWER_clamp]
|Voltage   I(typ)   I(min)   I(max)
-3.3V     82.87mA    74.06mA    118.1mA
-1.926V   41.79mA    34.09mA    64.67mA
-1.725V   35.77mA    28.77mA    56.95mA
-1.658V   33.78mA    27.04mA    54.31mA
-1.189V   20.27mA    15.49mA    35.28mA
-1.122V   18.35mA    13.94mA    32.42mA
-854mV    10.5mA     7.941mA    20.03mA
-586mV    2.349mA    2.531mA    4.384mA
-519mV    997.2uA    1.406mA    1.953mA
-452mV    344.2uA    549.2uA    685.9uA
-184mV    2.187uA    1.695uA    8.906uA
3.3V      0A         0A         0A
[Ramp]
| variable   typ   min   max
dV/dt_r   0.705/0.588n   0.507/0.758n   1.064/0.421n
dV/dt_f   0.685/1.008n   0.481/1.355n   0.965/0.726n
R_load = 50.000
[Rising Waveform]
R_fixture= 50.000
V_fixture= 0.0
V_fixture_min= 0.0
V_fixture_max= 0.0
|time   V(typ)   V(min)   V(max)
0s        43.91nV    99.25nV    528.4nV
685ps     -820.5uV   7.982uV    40.69mV
996ps     -20.28mV   -186.7uV   975.7mV
1.15ns    19.05mV    -447.5uV   1.309V
1.367ns   289.6mV    -13.97mV   1.537V
1.681ns   746.8mV    -13.81mV   1.668V
2.152ns   1.036V     209.6mV    1.738V
2.914ns   1.143V     696.1mV    1.767V
3.921ns   1.17V      821.5mV    1.772V
20ns      1.176V     844.4mV    1.773V
[Rising Waveform]
R_fixture= 50.000
V_fixture= 3.300
V_fixture_min= 3.140
V_fixture_max= 3.470
|time   V(typ)   V(min)   V(max)
0s        2.158V     2.338V     1.861V
492ps     2.158V     2.338V     1.868V
615ps     2.158V     2.338V     2.476V
808ps     2.161V     2.338V     3.097V
1.124ns   2.914V     2.338V     3.372V
1.301ns   3.098V     2.367V     3.409V
1.536ns   3.201V     2.797V     3.436V
2.023ns   3.263V     3.045V     3.459V
3.603ns   3.298V     3.128V     3.47V
20ns      3.3V       3.14V      3.47V
[Falling Waveform]
R_fixture= 50.000
V_fixture= 3.300
V_fixture_min= 3.140
V_fixture_max= 3.470
|time   V(typ)   V(min)   V(max)
0s        3.3V       3.14V      3.47V
671ps     3.298V     3.14V      3.503V
959ps     3.336V     3.139V     3.119V
1.189ns   3.312V     3.138V     2.664V
1.744ns   2.857V     3.164V     2.117V
2.116ns   2.57V      3.111V     1.972V
2.642ns   2.344V     2.884V     1.895V
3.461ns   2.205V     2.567V     1.867V
4.872ns   2.162V     2.38V      1.861V
20ns      2.158V     2.338V     1.861V
[Falling Waveform]
R_fixture= 50.000
V_fixture= 0.0
V_fixture_min= 0.0
V_fixture_max= 0.0
|time   V(typ)   V(min)   V(max)
0s        1.176V     844.4mV    1.773V
519ps     1.175V     844.4mV    1.762V
651ps     1.175V     844.5mV    1.086V
872ps     1.17V      844.2mV    374.2mV
1.111ns   539.4mV    843.6mV    101.5mV
1.475ns   133.7mV    825.9mV    26.79mV
1.737ns   51.85mV    366.8mV    11.72mV
1.919ns   30.59mV    214.3mV    6.477mV
2.924ns   2.939mV    16.91mV    382.9uV
20ns      67.95nV    166.9nV    608.1nV
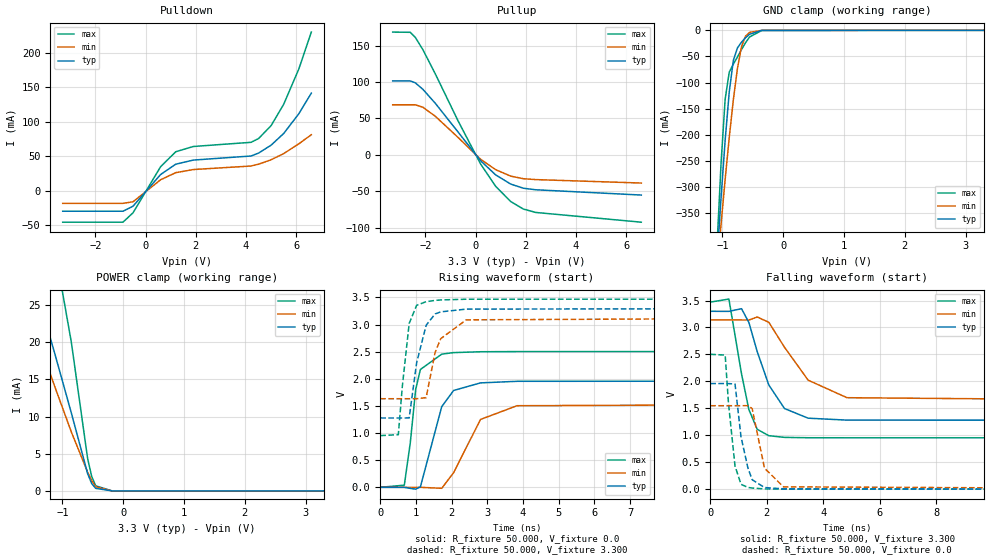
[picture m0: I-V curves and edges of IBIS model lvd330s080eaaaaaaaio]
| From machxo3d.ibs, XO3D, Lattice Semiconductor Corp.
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|   Model lvd330s080eaaaaaaaio
[Model] lvd330s080eaaaaaaaio
Model_type I/O
Polarity   Non-Inverting
Enable   Active-Low
Vinl =  0.800V
Vinh =  2.000V
Vmeas =  1.650V
Cref =  0.0F
Rref =  1.000M
Vref =  0.0V
C_comp   4.200pF   3.800pF   7.500pF
[Temperature Range]   25.000   0.105k   -40.000
[Voltage Range]   3.300V   3.140V   3.470V
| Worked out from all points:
|   slope of the pulldown table from 0 to 0.495 V, typ, clamps not added: 24.3 ohm
|   slope of the pullup table from 0 to 0.495 V, typ, clamps not added: 26.7 ohm
|   GND clamp passes 1 mA (typ) near -0.43 V on its own axis
|   POWER clamp passes 1 mA (typ) near -0.52 V on its own axis
|   rising waveform, R_fixture 50.000, V_fixture 0.0: 20-80 % time 467ps typ, 714ps min, 268ps max; typ from 0 V to 1.96 V
|   rising waveform, R_fixture 50.000, V_fixture 3.300: 20-80 % time 336ps typ, 426ps min, 229ps max; typ from 1.28 V to 3.3 V
|   falling waveform, R_fixture 50.000, V_fixture 3.300: 20-80 % time 854ps typ, 1.27ns min, 503ps max; typ from 3.3 V to 1.28 V
|   falling waveform, R_fixture 50.000, V_fixture 0.0: 20-80 % time 372ps typ, 451ps min, 268ps max; typ from 1.96 V to 0 V
[Pulldown]
|Voltage   I(typ)   I(min)   I(max)
-3.3V     -29.32mA   -17.9mA    -45.21mA
-900mV    -29.32mA   -17.9mA    -45.21mA
-500mV    -22.04mA   -15.61mA   -31.59mA
600mV     23.9mA     16.31mA    35.23mA
1.2V      38.8mA     26.54mA    56.81mA
1.9V      44.78mA    31.05mA    64.46mA
4.2V      50.68mA    36.17mA    70.51mA
4.5V      54.92mA    38.85mA    75.97mA
5V        66.4mA     45.23mA    94.76mA
5.5V      83.31mA    54.2mA     125.6mA
6.1V      111.8mA    68.27mA    176.5mA
6.6V      141.7mA    81.51mA    230.2mA
[Pullup]
|Voltage   I(typ)   I(min)   I(max)
-3.3V     101.4mA    68.64mA    168.4mA
-2.6V     101.4mA    68.64mA    168.1mA
-2.4V     98.8mA     68.64mA    161.1mA
-2.1V     89.93mA    65.34mA    144.4mA
-1.6V     70.55mA    52.78mA    110.8mA
-700mV    31.42mA    23.93mA    46.77mA
200mV     -8.086mA   -6.051mA   -12.55mA
800mV     -27.53mA   -20.35mA   -43.24mA
1.4V      -40.13mA   -29.21mA   -64.05mA
1.9V      -45.78mA   -32.75mA   -74.34mA
2.4V      -47.94mA   -33.97mA   -79.05mA
6.6V      -55.18mA   -38.69mA   -92.4mA
[GND_clamp]
|Voltage   I(typ)   I(min)   I(max)
-3.3V     -4.913A    -3.768A    -6.865A
-1.089V   -436.6mA   -458.9mA   -411.5mA
-1.022V   -318.8mA   -370mA     -253.2mA
-955mV    -210mA     -284.8mA   -131.4mA
-888mV    -117.9mA   -205.1mA   -80.02mA
-821mV    -57.76mA   -133.4mA   -64.74mA
-754mV    -33.88mA   -73.63mA   -51.23mA
-687mV    -22.76mA   -31.63mA   -36.92mA
-620mV    -14.21mA   -11.16mA   -23.73mA
-553mV    -7.411mA   -3.893mA   -12.67mA
-352mV    -131.3uA   -58.9uA    -219uA
3.3V      0A         0A         0A
[POWER_clamp]
|Voltage   I(typ)   I(min)   I(max)
-3.3V     82.87mA    74.06mA    118.1mA
-1.926V   41.79mA    34.09mA    64.67mA
-1.725V   35.77mA    28.77mA    56.95mA
-1.658V   33.78mA    27.04mA    54.31mA
-1.189V   20.27mA    15.49mA    35.28mA
-1.122V   18.35mA    13.94mA    32.42mA
-854mV    10.5mA     7.941mA    20.03mA
-586mV    2.349mA    2.531mA    4.384mA
-519mV    997.2uA    1.406mA    1.953mA
-452mV    344.2uA    549.2uA    685.9uA
-184mV    2.187uA    1.695uA    8.906uA
3.3V      0A         0A         0A
[Ramp]
| variable   typ   min   max
dV/dt_r   1.175/0.468n   0.929/0.713n   1.501/0.267n
dV/dt_f   1.213/0.850n   0.904/1.276n   1.510/0.504n
R_load = 50.000
[Rising Waveform]
R_fixture= 50.000
V_fixture= 0.0
V_fixture_min= 0.0
V_fixture_max= 0.0
|time   V(typ)   V(min)   V(max)
0s        28.46nV    68.59nV    322.9nV
674ps     -713uV     4.101uV    39.44mV
842ps     -19.42mV   4.101uV    823.9mV
992ps     -34.18mV   -98.13uV   1.803V
1.125ns   8.234mV    -466.3uV   2.172V
1.723ns   1.487V     -18.26mV   2.455V
2.056ns   1.785V     269.5mV    2.483V
2.81ns    1.925V     1.251V     2.499V
3.834ns   1.954V     1.504V     2.502V
20ns      1.959V     1.548V     2.502V
[Rising Waveform]
R_fixture= 50.000
V_fixture= 3.300
V_fixture_min= 3.140
V_fixture_max= 3.470
|time   V(typ)   V(min)   V(max)
0s        1.278V     1.633V     953.3mV
506ps     1.278V     1.633V     970.1mV
618ps     1.277V     1.633V     1.858V
810ps     1.279V     1.633V     3.019V
1.019ns   2.294V     1.633V     3.355V
1.286ns   2.987V     1.653V     3.422V
1.537ns   3.196V     2.486V     3.445V
1.695ns   3.234V     2.74V      3.454V
2.411ns   3.285V     3.087V     3.467V
20ns      3.3V       3.14V      3.47V
[Falling Waveform]
R_fixture= 50.000
V_fixture= 3.300
V_fixture_min= 3.140
V_fixture_max= 3.470
|time   V(typ)   V(min)   V(max)
0s        3.3V       3.14V      3.47V
660ps     3.299V     3.14V      3.527V
1.108ns   3.348V     3.139V     2.138V
1.369ns   3.091V     3.138V     1.475V
1.664ns   2.551V     3.194V     1.111V
2.075ns   1.932V     3.096V     991.7mV
2.63ns    1.496V     2.633V     960.8mV
3.469ns   1.317V     2.022V     954mV
4.846ns   1.281V     1.697V     953.2mV
20ns      1.278V     1.633V     953.1mV
[Falling Waveform]
R_fixture= 50.000
V_fixture= 0.0
V_fixture_min= 0.0
V_fixture_max= 0.0
|time   V(typ)   V(min)   V(max)
0s        1.959V     1.548V     2.502V
528ps     1.959V     1.548V     2.488V
647ps     1.958V     1.548V     1.582V
877ps     1.951V     1.548V     428.1mV
1.09ns    968.1mV    1.548V     90.33mV
1.334ns   393.7mV    1.549V     32.62mV
1.484ns   176.1mV    1.496V     20.55mV
1.921ns   30.23mV    390.4mV    4.748mV
2.593ns   6.144mV    43.52mV    603.9uV
20ns      65.09nV    142.4nV    503nV
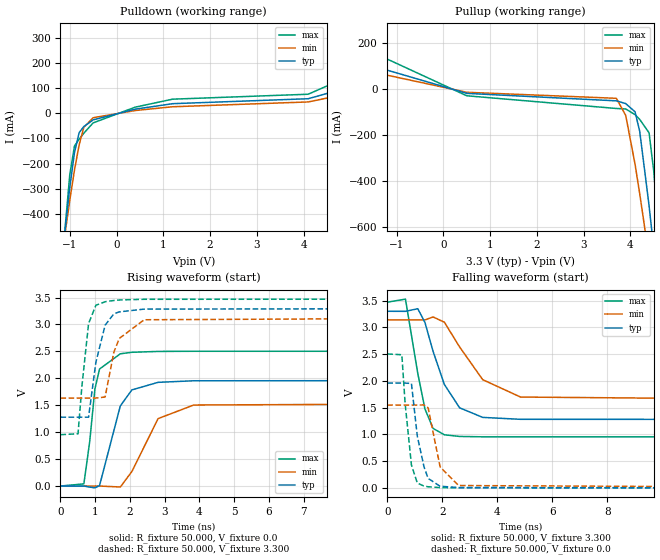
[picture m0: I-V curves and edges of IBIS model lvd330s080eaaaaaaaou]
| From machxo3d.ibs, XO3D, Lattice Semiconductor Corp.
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|   Model lvd330s080eaaaaaaaou
[Model] lvd330s080eaaaaaaaou
Model_type Output
Polarity   Non-Inverting
Enable   Active-High
Vmeas =  1.650V
Cref =  0.0F
Rref =  1.000M
Vref =  0.0V
C_comp   4.200pF   3.800pF   7.500pF
[Temperature Range]   25.000   0.105k   -40.000
[Voltage Range]   3.300V   3.140V   3.470V
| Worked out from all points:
|   slope of the pulldown table from 0 to 0.495 V, typ, clamps not added: 24.3 ohm
|   slope of the pullup table from 0 to 0.495 V, typ, clamps not added: 26.7 ohm
|   rising waveform, R_fixture 50.000, V_fixture 0.0: 20-80 % time 467ps typ, 714ps min, 268ps max; typ from 0 V to 1.96 V
|   rising waveform, R_fixture 50.000, V_fixture 3.300: 20-80 % time 336ps typ, 426ps min, 229ps max; typ from 1.28 V to 3.3 V
|   falling waveform, R_fixture 50.000, V_fixture 3.300: 20-80 % time 854ps typ, 1.27ns min, 503ps max; typ from 3.3 V to 1.28 V
|   falling waveform, R_fixture 50.000, V_fixture 0.0: 20-80 % time 372ps typ, 451ps min, 268ps max; typ from 1.96 V to 0 V
[Pulldown]
|Voltage   I(typ)   I(min)   I(max)
-3.3V     -4.914A    -3.768A    -6.866A
-1.1V     -463.2mA   -477mA     -456mA
-1V       -294.6mA   -346mA     -243.6mA
-900mV    -156.2mA   -226mA     -129.9mA
-800mV    -76.66mA   -125.5mA   -103mA
-700mV    -52.48mA   -55.46mA   -78.79mA
-500mV    -25.63mA   -17.18mA   -37.74mA
400mV     16.94mA    11.56mA    24.96mA
1.2V      38.8mA     26.54mA    56.81mA
4.1V      58.57mA    45.76mA    76.5mA
5.4V      126.5mA    95.45mA    183.4mA
6.6V      224.6mA    160.6mA    342mA
[Pullup]
|Voltage   I(typ)   I(min)   I(max)
-3.3V     164.8mA    117.3mA    263.7mA
-2.5V     159.7mA    117.3mA    252.7mA
500mV     -18.69mA   -13.91mA   -29.17mA
3.7V      -51.21mA   -40.19mA   -84.43mA
3.9V      -63.12mA   -114.5mA   -86.54mA
4.1V      -98.87mA   -327.4mA   -111.3mA
4.2V      -184.4mA   -456.5mA   -132.1mA
4.4V      -508.6mA   -733.1mA   -190.5mA
4.5V      -694.7mA   -876.4mA   -357.9mA
4.6V      -886.7mA   -1.022A    -603.9mA
4.7V      -1.083A    -1.169A    -873mA
6.6V      -4.969A    -4.052A    -6.451A
[Ramp]
| variable   typ   min   max
dV/dt_r   1.175/0.468n   0.929/0.713n   1.501/0.267n
dV/dt_f   1.213/0.850n   0.904/1.276n   1.510/0.504n
R_load = 50.000
[Rising Waveform]
R_fixture= 50.000
V_fixture= 0.0
V_fixture_min= 0.0
V_fixture_max= 0.0
|time   V(typ)   V(min)   V(max)
0s        28.46nV    68.59nV    322.9nV
674ps     -713uV     4.101uV    39.44mV
842ps     -19.42mV   4.101uV    823.9mV
992ps     -34.18mV   -98.14uV   1.803V
1.125ns   8.234mV    -466.3uV   2.172V
1.723ns   1.487V     -18.26mV   2.455V
2.056ns   1.785V     269.5mV    2.483V
2.81ns    1.925V     1.251V     2.499V
3.834ns   1.954V     1.504V     2.502V
20ns      1.959V     1.548V     2.502V
[Rising Waveform]
R_fixture= 50.000
V_fixture= 3.300
V_fixture_min= 3.140
V_fixture_max= 3.470
|time   V(typ)   V(min)   V(max)
0s        1.278V     1.633V     953.3mV
506ps     1.278V     1.633V     970.1mV
614ps     1.278V     1.633V     1.83V
809ps     1.278V     1.633V     3.015V
1.019ns   2.294V     1.633V     3.355V
1.286ns   2.987V     1.653V     3.422V
1.537ns   3.196V     2.486V     3.445V
1.695ns   3.234V     2.74V      3.454V
2.411ns   3.285V     3.087V     3.467V
20ns      3.3V       3.14V      3.47V
[Falling Waveform]
R_fixture= 50.000
V_fixture= 3.300
V_fixture_min= 3.140
V_fixture_max= 3.470
|time   V(typ)   V(min)   V(max)
0s        3.3V       3.14V      3.47V
660ps     3.299V     3.14V      3.527V
1.108ns   3.348V     3.139V     2.138V
1.369ns   3.091V     3.138V     1.475V
1.664ns   2.551V     3.194V     1.111V
2.075ns   1.932V     3.096V     991.7mV
2.63ns    1.496V     2.633V     960.8mV
3.469ns   1.317V     2.022V     954mV
4.846ns   1.281V     1.697V     953.2mV
20ns      1.278V     1.633V     953.1mV
[Falling Waveform]
R_fixture= 50.000
V_fixture= 0.0
V_fixture_min= 0.0
V_fixture_max= 0.0
|time   V(typ)   V(min)   V(max)
0s        1.959V     1.548V     2.502V
528ps     1.959V     1.548V     2.488V
647ps     1.958V     1.548V     1.582V
877ps     1.951V     1.548V     428.1mV
1.09ns    968.1mV    1.548V     90.33mV
1.334ns   393.7mV    1.549V     32.62mV
1.484ns   176.1mV    1.496V     20.55mV
1.921ns   30.23mV    390.4mV    4.748mV
2.593ns   6.144mV    43.52mV    603.9uV
20ns      65.09nV    142.4nV    503nV
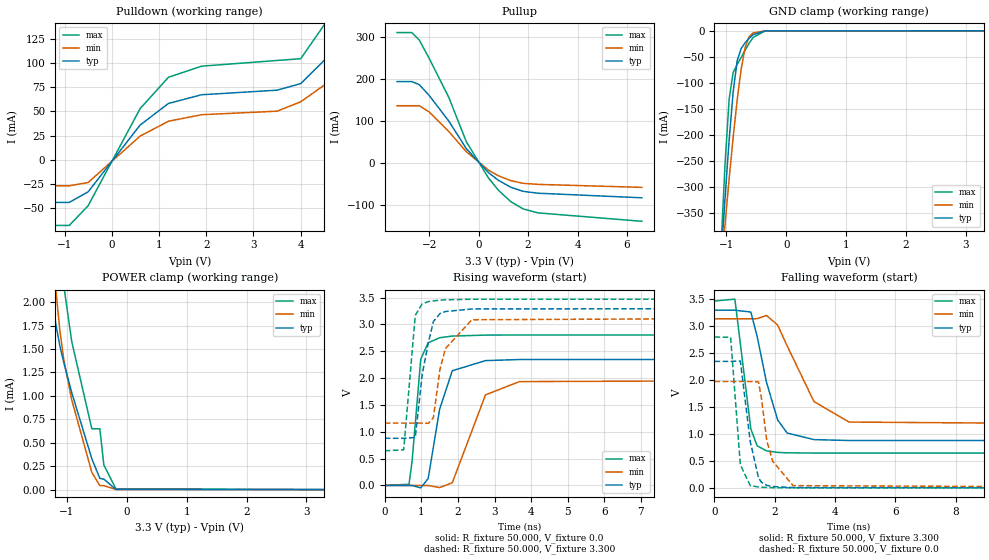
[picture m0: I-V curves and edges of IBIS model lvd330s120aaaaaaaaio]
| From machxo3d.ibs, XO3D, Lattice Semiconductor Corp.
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|   Model lvd330s120aaaaaaaaio
[Model] lvd330s120aaaaaaaaio
Model_type I/O
Polarity   Non-Inverting
Enable   Active-Low
Vinl =  0.800V
Vinh =  2.000V
Vmeas =  1.650V
Cref =  0.0F
Rref =  1.000M
Vref =  0.0V
C_comp   4.200pF   3.800pF   7.500pF
[Temperature Range]   25.000   0.105k   -40.000
[Voltage Range]   3.300V   3.140V   3.470V
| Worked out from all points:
|   slope of the pulldown table from 0 to 0.495 V, typ, clamps not added: 16.2 ohm
|   slope of the pullup table from 0 to 0.495 V, typ, clamps not added: 17.8 ohm
|   GND clamp passes 1 mA (typ) near -0.43 V on its own axis
|   POWER clamp passes 1 mA (typ) near -0.91 V on its own axis
|   rising waveform, R_fixture 50.000, V_fixture 0.0: 20-80 % time 364ps typ, 594ps min, 199ps max; typ from 0 V to 2.35 V
|   rising waveform, R_fixture 50.000, V_fixture 3.300: 20-80 % time 320ps typ, 412ps min, 206ps max; typ from 0.878 V to 3.3 V
|   falling waveform, R_fixture 50.000, V_fixture 3.300: 20-80 % time 611ps typ, 1.05ns min, 342ps max; typ from 3.3 V to 0.878 V
|   falling waveform, R_fixture 50.000, V_fixture 0.0: 20-80 % time 346ps typ, 442ps min, 235ps max; typ from 2.35 V to 0 V
[Pulldown]
|Voltage   I(typ)   I(min)   I(max)
-3.3V     -43.98mA   -26.85mA   -67.81mA
-900mV    -43.98mA   -26.85mA   -67.81mA
-500mV    -33.06mA   -23.42mA   -47.39mA
600mV     35.86mA    24.47mA    52.84mA
1.2V      58.2mA     39.81mA    85.22mA
1.9V      67.18mA    46.57mA    96.69mA
3.5V      71.92mA    50.22mA    102.6mA
4V        78.72mA    59.91mA    104.4mA
5V        126.9mA    94.39mA    174.7mA
5.3V      146.9mA    108.3mA    207.3mA
5.9V      198.1mA    141.5mA    291.1mA
6.6V      273.7mA    187.1mA    418.1mA
[Pullup]
|Voltage   I(typ)   I(min)   I(max)
-3.3V     193.1mA    135.8mA    309.5mA
-2.7V     193.1mA    135.8mA    309.5mA
-2.4V     185.8mA    135.8mA    291.7mA
-2V       160.3mA    121mA      248.4mA
-1.2V     98.91mA    74.26mA    154.9mA
-500mV    34.16mA    26.7mA     50.66mA
400mV     -23.03mA   -17.17mA   -35.88mA
800mV     -41.29mA   -30.53mA   -64.86mA
1.3V      -57.73mA   -42.14mA   -91.85mA
1.8V      -67.47mA   -48.45mA   -109.2mA
2.4V      -71.91mA   -50.95mA   -118.6mA
6.6V      -82.77mA   -58.04mA   -138.6mA
[GND_clamp]
|Voltage   I(typ)   I(min)   I(max)
-3.3V     -4.913A    -3.768A    -6.865A
-1.089V   -436.6mA   -458.9mA   -411.5mA
-1.022V   -318.8mA   -370mA     -253.2mA
-955mV    -210mA     -284.8mA   -131.4mA
-888mV    -117.9mA   -205.1mA   -80.02mA
-821mV    -57.76mA   -133.4mA   -64.74mA
-754mV    -33.88mA   -73.63mA   -51.23mA
-687mV    -22.76mA   -31.63mA   -36.92mA
-620mV    -14.21mA   -11.16mA   -23.73mA
-553mV    -7.411mA   -3.893mA   -12.67mA
-352mV    -131.3uA   -58.9uA    -219uA
3.3V      0A         0A         0A
[POWER_clamp]
|Voltage   I(typ)   I(min)   I(max)
-3.3V     32.67mA    26.87mA    52.85mA
-1.323V   2.804mA    3.246mA    8.665mA
-1.256V   2.134mA    2.67mA     6.124mA
-1.189V   1.77mA     2.147mA    4.184mA
-1.122V   1.54mA     1.71mA     2.893mA
-1.055V   1.357mA    1.39mA     2.18mA
-921mV    1.034mA    956.5uA    1.578mA
-586mV    330uA      184.5uA    649.8uA
-452mV    119.7uA    42.63uA    649.8uA
-385mV    112.2uA    42.63uA    262.6uA
-184mV    2.18uA     1.689uA    8.903uA
3.3V      0A         0A         0A
[Ramp]
| variable   typ   min   max
dV/dt_r   1.409/0.363n   1.186/0.594n   1.681/0.197n
dV/dt_f   1.453/0.613n   1.187/1.048n   1.695/0.343n
R_load = 50.000
[Rising Waveform]
R_fixture= 50.000
V_fixture= 0.0
V_fixture_min= 0.0
V_fixture_max= 0.0
|time   V(typ)   V(min)   V(max)
0s        21.06nV    52.4nV     232.5nV
662ps     -522.6uV   527.1nV    22.12mV
746ps     -1.434mV   527.1nV    446.8mV
983ps     -44.83mV   -65.47uV   2.351V
1.187ns   130.4mV    -925.2uV   2.657V
1.499ns   1.418V     -39.53mV   2.751V
1.845ns   2.136V     49.26mV    2.782V
2.754ns   2.325V     1.687V     2.8V
3.681ns   2.345V     1.934V     2.802V
20ns      2.349V     1.976V     2.802V
[Rising Waveform]
R_fixture= 50.000
V_fixture= 3.300
V_fixture_min= 3.140
V_fixture_max= 3.470
|time   V(typ)   V(min)   V(max)
0s        878.1mV    1.161V     645.8mV
517ps     878.1mV    1.161V     664.1mV
834ps     892.6mV    1.161V     3.168V
1.023ns   2.068V     1.161V     3.384V
1.194ns   2.668V     1.157V     3.423V
1.329ns   3.051V     1.264V     3.438V
1.509ns   3.201V     2.162V     3.45V
1.657ns   3.239V     2.548V     3.457V
2.381ns   3.287V     3.086V     3.468V
20ns      3.3V       3.14V      3.47V
[Falling Waveform]
R_fixture= 50.000
V_fixture= 3.300
V_fixture_min= 3.140
V_fixture_max= 3.470
|time   V(typ)   V(min)   V(max)
0s        3.3V       3.14V      3.47V
676ps     3.299V     3.14V      3.505V
1.204ns   3.266V     3.139V     1.095V
1.414ns   2.813V     3.142V     780.5mV
1.725ns   1.958V     3.202V     686.5mV
2.093ns   1.263V     3.024V     658.2mV
2.405ns   1.02V      2.641V     650.6mV
3.296ns   895.9mV    1.604V     646.1mV
4.463ns   879.7mV    1.222V     645.8mV
20ns      878mV      1.161V     645.8mV
[Falling Waveform]
R_fixture= 50.000
V_fixture= 0.0
V_fixture_min= 0.0
V_fixture_max= 0.0
|time   V(typ)   V(min)   V(max)
0s        2.349V     1.976V     2.802V
535ps     2.349V     1.976V     2.795V
857ps     2.356V     1.976V     427.9mV
1.186ns   859.5mV    1.976V     41.96mV
1.46ns    185.2mV    1.968V     16.08mV
1.554ns   105.4mV    1.672V     11.85mV
1.734ns   45.92mV    871.8mV    7.002mV
1.928ns   24.82mV    496.5mV    3.499mV
2.605ns   5.277mV    41.08mV    471.9uV
20ns      65.2nV     118.2nV    412.7nV
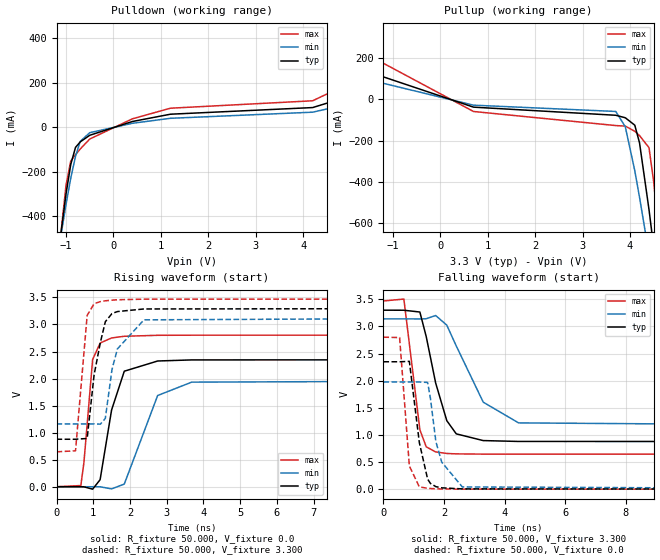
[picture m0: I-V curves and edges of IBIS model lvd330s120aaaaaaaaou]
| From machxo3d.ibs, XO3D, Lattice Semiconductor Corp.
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|   Model lvd330s120aaaaaaaaou
[Model] lvd330s120aaaaaaaaou
Model_type Output
Polarity   Non-Inverting
Enable   Active-High
Vmeas =  1.650V
Cref =  0.0F
Rref =  1.000M
Vref =  0.0V
C_comp   4.200pF   3.800pF   7.500pF
[Temperature Range]   25.000   0.105k   -40.000
[Voltage Range]   3.300V   3.140V   3.470V
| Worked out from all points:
|   slope of the pulldown table from 0 to 0.495 V, typ, clamps not added: 16.2 ohm
|   slope of the pullup table from 0 to 0.495 V, typ, clamps not added: 17.8 ohm
|   rising waveform, R_fixture 50.000, V_fixture 0.0: 20-80 % time 364ps typ, 594ps min, 199ps max; typ from 0 V to 2.35 V
|   rising waveform, R_fixture 50.000, V_fixture 3.300: 20-80 % time 320ps typ, 412ps min, 206ps max; typ from 0.878 V to 3.3 V
|   falling waveform, R_fixture 50.000, V_fixture 3.300: 20-80 % time 611ps typ, 1.05ns min, 342ps max; typ from 3.3 V to 0.878 V
|   falling waveform, R_fixture 50.000, V_fixture 0.0: 20-80 % time 346ps typ, 442ps min, 235ps max; typ from 2.35 V to 0 V
[Pulldown]
|Voltage   I(typ)   I(min)   I(max)
-3.3V     -4.914A    -3.768A    -6.866A
-1.1V     -466.5mA   -478.5mA   -464.3mA
-1V       -301mA     -348.2mA   -261.7mA
-900mV    -168mA     -229.6mA   -152.5mA
-800mV    -91.31mA   -131.6mA   -124.1mA
-700mV    -66.41mA   -64.15mA   -98.36mA
-500mV    -36.65mA   -24.99mA   -53.53mA
400mV     25.4mA     17.33mA    37.45mA
1.2V      58.2mA     39.81mA    85.22mA
4.2V      88.14mA    67.34mA    118.7mA
5.3V      160.3mA    120.1mA    230.5mA
6.6V      306.3mA    216.5mA    466.7mA
[Pullup]
|Voltage   I(typ)   I(min)   I(max)
-3.3V     215.2mA    151.1mA    348.8mA
-2.5V     210.4mA    151.1mA    336mA
700mV     -37.16mA   -27.54mA   -58.24mA
3.7V      -76.59mA   -58.11mA   -126.6mA
3.9V      -88.69mA   -132.5mA   -129.1mA
4.1V      -124.6mA   -345.5mA   -154.2mA
4.2V      -210.2mA   -474.8mA   -175.2mA
4.4V      -534.7mA   -751.5mA   -233.9mA
4.5V      -720.8mA   -894.9mA   -401.4mA
4.6V      -913mA     -1.04A     -647.5mA
4.7V      -1.109A    -1.187A    -916.8mA
6.6V      -4.996A    -4.072A    -6.497A
[Ramp]
| variable   typ   min   max
dV/dt_r   1.409/0.363n   1.186/0.594n   1.681/0.197n
dV/dt_f   1.453/0.613n   1.187/1.048n   1.695/0.343n
R_load = 50.000
[Rising Waveform]
R_fixture= 50.000
V_fixture= 0.0
V_fixture_min= 0.0
V_fixture_max= 0.0
|time   V(typ)   V(min)   V(max)
0s        21.06nV    52.4nV     232.5nV
662ps     -522.6uV   527.8nV    22.12mV
746ps     -1.434mV   527.8nV    446.8mV
983ps     -44.83mV   -65.47uV   2.351V
1.187ns   130.4mV    -934.2uV   2.657V
1.499ns   1.418V     -39.53mV   2.751V
1.845ns   2.136V     49.26mV    2.782V
2.754ns   2.325V     1.687V     2.8V
3.681ns   2.345V     1.934V     2.802V
20ns      2.349V     1.976V     2.802V
[Rising Waveform]
R_fixture= 50.000
V_fixture= 3.300
V_fixture_min= 3.140
V_fixture_max= 3.470
|time   V(typ)   V(min)   V(max)
0s        878.1mV    1.161V     645.8mV
517ps     878.1mV    1.161V     664.1mV
834ps     892.6mV    1.161V     3.168V
1.023ns   2.068V     1.161V     3.384V
1.194ns   2.668V     1.157V     3.423V
1.329ns   3.051V     1.264V     3.438V
1.509ns   3.201V     2.162V     3.45V
1.657ns   3.239V     2.548V     3.457V
2.381ns   3.287V     3.086V     3.468V
20ns      3.3V       3.14V      3.47V
[Falling Waveform]
R_fixture= 50.000
V_fixture= 3.300
V_fixture_min= 3.140
V_fixture_max= 3.470
|time   V(typ)   V(min)   V(max)
0s        3.3V       3.14V      3.47V
676ps     3.299V     3.14V      3.505V
1.204ns   3.266V     3.139V     1.095V
1.414ns   2.813V     3.142V     780.5mV
1.725ns   1.958V     3.202V     686.5mV
2.093ns   1.263V     3.024V     658.2mV
2.405ns   1.02V      2.641V     650.6mV
3.296ns   895.9mV    1.604V     646.1mV
4.463ns   879.7mV    1.222V     645.8mV
20ns      878mV      1.161V     645.8mV
[Falling Waveform]
R_fixture= 50.000
V_fixture= 0.0
V_fixture_min= 0.0
V_fixture_max= 0.0
|time   V(typ)   V(min)   V(max)
0s        2.349V     1.976V     2.802V
535ps     2.349V     1.976V     2.795V
857ps     2.356V     1.976V     427.9mV
1.186ns   859.5mV    1.976V     41.96mV
1.46ns    185.2mV    1.968V     16.08mV
1.554ns   105.4mV    1.672V     11.85mV
1.734ns   45.92mV    871.8mV    7.002mV
1.928ns   24.82mV    496.5mV    3.499mV
2.605ns   5.277mV    41.08mV    467.6uV
20ns      65.2nV     118.2nV    412.7nV
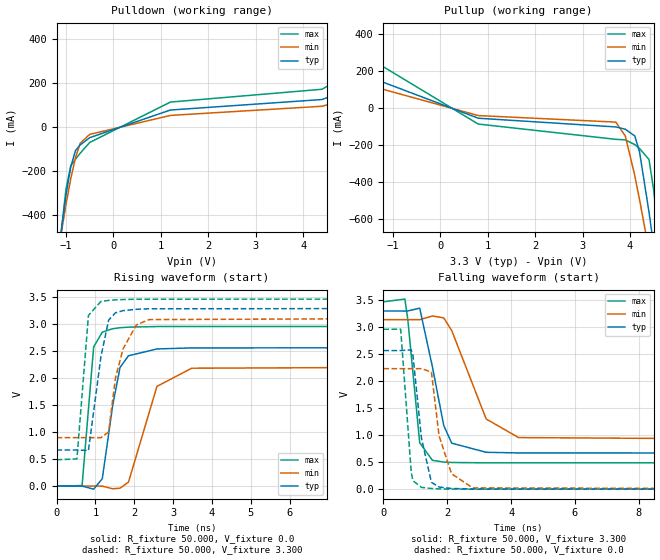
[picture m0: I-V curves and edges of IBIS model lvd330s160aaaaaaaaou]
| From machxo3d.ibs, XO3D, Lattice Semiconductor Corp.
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|   Model lvd330s160aaaaaaaaou
[Model] lvd330s160aaaaaaaaou
Model_type Output
Polarity   Non-Inverting
Enable   Active-High
Vmeas =  1.650V
Cref =  0.0F
Rref =  1.000M
Vref =  0.0V
C_comp   4.200pF   3.800pF   7.500pF
[Temperature Range]   25.000   0.105k   -40.000
[Voltage Range]   3.300V   3.140V   3.470V
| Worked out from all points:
|   slope of the pulldown table from 0 to 0.495 V, typ, clamps not added: 12.2 ohm
|   slope of the pullup table from 0 to 0.495 V, typ, clamps not added: 13.4 ohm
|   rising waveform, R_fixture 50.000, V_fixture 0.0: 20-80 % time 306ps typ, 516ps min, 165ps max; typ from 0 V to 2.57 V
|   rising waveform, R_fixture 50.000, V_fixture 3.300: 20-80 % time 312ps typ, 411ps min, 192ps max; typ from 0.669 V to 3.3 V
|   falling waveform, R_fixture 50.000, V_fixture 3.300: 20-80 % time 496ps typ, 874ps min, 276ps max; typ from 3.3 V to 0.669 V
|   falling waveform, R_fixture 50.000, V_fixture 0.0: 20-80 % time 338ps typ, 438ps min, 220ps max; typ from 2.57 V to 0 V
[Pulldown]
|Voltage   I(typ)   I(min)   I(max)
-3.3V     -4.914A    -3.769A    -6.866A
-1.1V     -469.8mA   -480.1mA   -472.7mA
-1V       -307.4mA   -350.5mA   -279.8mA
-900mV    -179.8mA   -233.2mA   -175.1mA
-800mV    -106mA     -137.7mA   -145.2mA
-700mV    -80.34mA   -72.85mA   -117.9mA
-500mV    -47.66mA   -32.8mA    -69.33mA
1.2V      77.59mA    53.08mA    113.6mA
4.4V      125.2mA    94.73mA    171.7mA
5.3V      200.7mA    149.4mA    288.1mA
6.1V      305.4mA    219.8mA    456.5mA
6.6V      388.1mA    272.4mA    591.4mA
[Pullup]
|Voltage   I(typ)   I(min)   I(max)
-3.3V     266mA      185.1mA    434.7mA
-2.4V     254.5mA    184.9mA    407.1mA
800mV     -55.05mA   -40.71mA   -86.48mA
3.7V      -102mA     -76.03mA   -168.8mA
3.9V      -114.3mA   -150.6mA   -171.6mA
4.1V      -150.4mA   -363.7mA   -197mA
4.2V      -236.1mA   -493mA     -218.2mA
4.4V      -560.7mA   -769.8mA   -277.2mA
4.5V      -747mA     -913.3mA   -444.9mA
4.6V      -939.2mA   -1.059A    -691.2mA
4.7V      -1.135A    -1.206A    -960.6mA
6.6V      -5.024A    -4.091A    -6.543A
[Ramp]
| variable   typ   min   max
dV/dt_r   1.541/0.305n   1.340/0.513n   1.777/0.164n
dV/dt_f   1.578/0.498n   1.345/0.874n   1.789/0.276n
R_load = 50.000
[Rising Waveform]
R_fixture= 50.000
V_fixture= 0.0
V_fixture_min= 0.0
V_fixture_max= 0.0
|time   V(typ)   V(min)   V(max)
0s        16.71nV    42.4nV     181.6nV
658ps     -471.4uV   -717nV     9.17mV
956ps     -57.44mV   -61.91uV   2.582V
1.179ns   137.4mV    -880.6uV   2.857V
1.446ns   1.495V     -50.5mV    2.92V
1.636ns   2.202V     -38.94mV   2.938V
1.853ns   2.418V     73.11mV    2.949V
2.586ns   2.544V     1.85V      2.96V
3.481ns   2.564V     2.187V     2.961V
20ns      2.568V     2.233V     2.961V
[Rising Waveform]
R_fixture= 50.000
V_fixture= 3.300
V_fixture_min= 3.140
V_fixture_max= 3.470
|time   V(typ)   V(min)   V(max)
0s        669.4mV    899.2mV    487.7mV
525ps     669.4mV    899.2mV    504.2mV
822ps     659.7mV    899.2mV    3.167V
1.144ns   2.404V     898.5mV    3.426V
1.342ns   3.079V     1.005V     3.445V
1.516ns   3.215V     2V         3.455V
1.715ns   3.255V     2.548V     3.461V
2.056ns   3.28V      2.991V     3.467V
2.381ns   3.29V      3.089V     3.468V
20ns      3.3V       3.14V      3.47V
[Falling Waveform]
R_fixture= 50.000
V_fixture= 3.300
V_fixture_min= 3.140
V_fixture_max= 3.470
|time   V(typ)   V(min)   V(max)
0s        3.3V       3.14V      3.47V
673ps     3.299V     3.14V      3.521V
762ps     3.3V       3.14V      3.157V
1.137ns   3.353V     3.139V     860.1mV
1.536ns   2.265V     3.208V     534.5mV
1.889ns   1.183V     3.173V     501.8mV
2.14ns    852.3mV    2.939V     493.8mV
3.219ns   682.8mV    1.3V       487.7mV
4.235ns   671mV      955.7mV    487.5mV
20ns      669.4mV    899.2mV    487.5mV
[Falling Waveform]
R_fixture= 50.000
V_fixture= 0.0
V_fixture_min= 0.0
V_fixture_max= 0.0
|time   V(typ)   V(min)   V(max)
0s        2.568V     2.233V     2.961V
541ps     2.567V     2.233V     2.963V
872ps     2.58V      2.232V     311.3mV
927ps     2.471V     2.232V     157mV
1.192ns   945.9mV    2.233V     33.63mV
1.505ns   126.3mV    2.168V     11.71mV
1.745ns   39.28mV    985.6mV    5.194mV
2.134ns   12.82mV    286.6mV    1.387mV
2.798ns   3.046mV    22.87mV    199.4uV
20ns      62.75nV    95.73nV    343.9nV
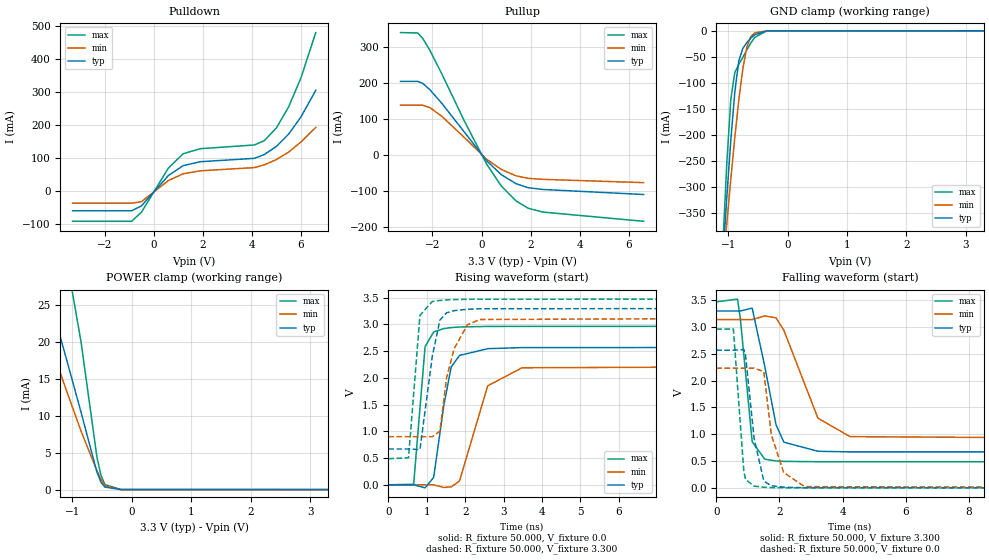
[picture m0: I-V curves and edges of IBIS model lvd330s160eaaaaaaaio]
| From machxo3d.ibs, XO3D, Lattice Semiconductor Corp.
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|   Model lvd330s160eaaaaaaaio
[Model] lvd330s160eaaaaaaaio
Model_type I/O
Polarity   Non-Inverting
Enable   Active-Low
Vinl =  0.800V
Vinh =  2.000V
Vmeas =  1.650V
Cref =  0.0F
Rref =  1.000M
Vref =  0.0V
C_comp   4.200pF   3.800pF   7.500pF
[Temperature Range]   25.000   0.105k   -40.000
[Voltage Range]   3.300V   3.140V   3.470V
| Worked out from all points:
|   slope of the pulldown table from 0 to 0.495 V, typ, clamps not added: 12.2 ohm
|   slope of the pullup table from 0 to 0.495 V, typ, clamps not added: 13.4 ohm
|   GND clamp passes 1 mA (typ) near -0.43 V on its own axis
|   POWER clamp passes 1 mA (typ) near -0.52 V on its own axis
|   rising waveform, R_fixture 50.000, V_fixture 0.0: 20-80 % time 306ps typ, 516ps min, 165ps max; typ from 0 V to 2.57 V
|   rising waveform, R_fixture 50.000, V_fixture 3.300: 20-80 % time 312ps typ, 411ps min, 192ps max; typ from 0.669 V to 3.3 V
|   falling waveform, R_fixture 50.000, V_fixture 3.300: 20-80 % time 496ps typ, 874ps min, 276ps max; typ from 3.3 V to 0.669 V
|   falling waveform, R_fixture 50.000, V_fixture 0.0: 20-80 % time 338ps typ, 438ps min, 220ps max; typ from 2.57 V to 0 V
[Pulldown]
|Voltage   I(typ)   I(min)   I(max)
-3.3V     -58.64mA   -35.81mA   -90.41mA
-900mV    -58.64mA   -35.81mA   -90.41mA
-500mV    -44.08mA   -31.23mA   -63.19mA
600mV     47.81mA    32.63mA    70.46mA
1.2V      77.59mA    53.08mA    113.6mA
1.9V      89.57mA    62.1mA     128.9mA
4.1V      99.73mA    71.79mA    140.1mA
4.5V      111mA      80mA       152.9mA
5V        135.8mA    95.99mA    191.8mA
5.5V      173.4mA    119mA      255.7mA
6V        225.2mA    149.3mA    343.4mA
6.6V      305.2mA    193.3mA    479.6mA
[Pullup]
|Voltage   I(typ)   I(min)   I(max)
-3.3V     203.9mA    137.7mA    339.4mA
-2.6V     203.9mA    137.7mA    338.3mA
-2.4V     198.4mA    137.7mA    323.7mA
-2.1V     180.4mA    130.9mA    289.7mA
-1.6V     141.3mA    105.6mA    221.9mA
-700mV    62.84mA    47.87mA    93.53mA
200mV     -16.17mA   -12.1mA    -25.1mA
800mV     -55.05mA   -40.71mA   -86.48mA
1.4V      -80.26mA   -58.42mA   -128.1mA
1.9V      -91.56mA   -65.51mA   -148.7mA
2.5V      -96.41mA   -68.28mA   -159.2mA
6.6V      -110.4mA   -77.39mA   -184.8mA
[GND_clamp]
|Voltage   I(typ)   I(min)   I(max)
-3.3V     -4.913A    -3.768A    -6.865A
-1.089V   -436.6mA   -458.9mA   -411.5mA
-1.022V   -318.8mA   -370mA     -253.2mA
-955mV    -210mA     -284.8mA   -131.4mA
-888mV    -117.9mA   -205.1mA   -80.02mA
-821mV    -57.76mA   -133.4mA   -64.74mA
-754mV    -33.88mA   -73.63mA   -51.23mA
-687mV    -22.76mA   -31.63mA   -36.92mA
-620mV    -14.21mA   -11.16mA   -23.73mA
-553mV    -7.411mA   -3.893mA   -12.67mA
-352mV    -131.3uA   -58.9uA    -219uA
3.3V      0A         0A         0A
[POWER_clamp]
|Voltage   I(typ)   I(min)   I(max)
-3.3V     82.87mA    74.06mA    118.1mA
-1.926V   41.79mA    34.09mA    64.67mA
-1.725V   35.77mA    28.77mA    56.95mA
-1.658V   33.78mA    27.04mA    54.31mA
-1.189V   20.27mA    15.49mA    35.28mA
-1.122V   18.35mA    13.94mA    32.42mA
-854mV    10.5mA     7.941mA    20.03mA
-586mV    2.349mA    2.531mA    4.384mA
-519mV    997.2uA    1.406mA    1.953mA
-452mV    344.2uA    549.2uA    685.9uA
-184mV    2.187uA    1.695uA    8.906uA
3.3V      0A         0A         0A
[Ramp]
| variable   typ   min   max
dV/dt_r   1.541/0.305n   1.340/0.513n   1.777/0.164n
dV/dt_f   1.578/0.498n   1.345/0.874n   1.789/0.276n
R_load = 50.000
[Rising Waveform]
R_fixture= 50.000
V_fixture= 0.0
V_fixture_min= 0.0
V_fixture_max= 0.0
|time   V(typ)   V(min)   V(max)
0s        16.71nV    42.4nV     181.6nV
658ps     -471.4uV   -716.2nV   9.17mV
956ps     -57.44mV   -61.91uV   2.582V
1.179ns   137.4mV    -880.5uV   2.857V
1.446ns   1.495V     -50.5mV    2.92V
1.636ns   2.202V     -38.94mV   2.938V
1.853ns   2.418V     73.11mV    2.949V
2.586ns   2.544V     1.85V      2.96V
3.481ns   2.564V     2.187V     2.961V
20ns      2.568V     2.233V     2.961V
[Rising Waveform]
R_fixture= 50.000
V_fixture= 3.300
V_fixture_min= 3.140
V_fixture_max= 3.470
|time   V(typ)   V(min)   V(max)
0s        669.4mV    899.2mV    487.7mV
525ps     669.4mV    899.2mV    504.2mV
822ps     659.7mV    899.2mV    3.167V
1.144ns   2.404V     898.5mV    3.426V
1.342ns   3.079V     1.005V     3.445V
1.516ns   3.215V     2V         3.455V
1.715ns   3.255V     2.548V     3.461V
2.056ns   3.28V      2.991V     3.467V
2.381ns   3.29V      3.089V     3.468V
20ns      3.3V       3.14V      3.47V
[Falling Waveform]
R_fixture= 50.000
V_fixture= 3.300
V_fixture_min= 3.140
V_fixture_max= 3.470
|time   V(typ)   V(min)   V(max)
0s        3.3V       3.14V      3.47V
673ps     3.299V     3.14V      3.521V
762ps     3.3V       3.14V      3.157V
1.137ns   3.353V     3.139V     860.1mV
1.536ns   2.265V     3.208V     534.5mV
1.892ns   1.177V     3.172V     501.8mV
2.14ns    852.3mV    2.939V     493.8mV
3.219ns   682.8mV    1.3V       487.7mV
4.235ns   671mV      955.7mV    487.5mV
20ns      669.4mV    899.2mV    487.5mV
[Falling Waveform]
R_fixture= 50.000
V_fixture= 0.0
V_fixture_min= 0.0
V_fixture_max= 0.0
|time   V(typ)   V(min)   V(max)
0s        2.568V     2.233V     2.961V
541ps     2.567V     2.233V     2.963V
872ps     2.58V      2.232V     311.3mV
927ps     2.471V     2.232V     157mV
1.197ns   928.3mV    2.233V     32.79mV
1.505ns   126.3mV    2.168V     11.16mV
1.745ns   39.28mV    985.6mV    5.335mV
2.134ns   12.82mV    286.6mV    1.439mV
2.798ns   3.046mV    22.87mV    216.7uV
20ns      62.75nV    95.73nV    343.9nV
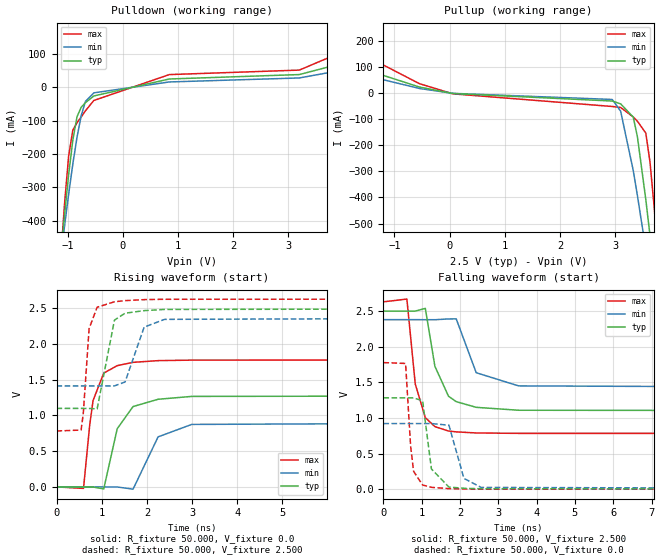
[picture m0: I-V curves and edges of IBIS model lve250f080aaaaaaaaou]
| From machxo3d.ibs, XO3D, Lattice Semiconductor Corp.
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|   Model lve250f080aaaaaaaaou
[Model] lve250f080aaaaaaaaou
Model_type Output
Polarity   Non-Inverting
Enable   Active-High
Vmeas =  1.250V
Cref =  3.000pF
Rref =  50.000
Vref =  1.250V
C_comp   4.200pF   3.800pF   7.500pF
[Temperature Range]   25.000   0.105k   -40.000
[Voltage Range]   2.500V   2.380V   2.630V
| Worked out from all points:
|   slope of the pulldown table from 0 to 0.375 V, typ, clamps not added: 27.2 ohm
|   slope of the pullup table from 0 to 0.375 V, typ, clamps not added: 32.5 ohm
|   rising waveform, R_fixture 50.000, V_fixture 0.0: 20-80 % time 367ps typ, 457ps min, 225ps max; typ from 0 V to 1.28 V
|   rising waveform, R_fixture 50.000, V_fixture 2.500: 20-80 % time 205ps typ, 303ps min, 127ps max; typ from 1.1 V to 2.5 V
|   falling waveform, R_fixture 50.000, V_fixture 2.500: 20-80 % time 393ps typ, 472ps min, 286ps max; typ from 2.5 V to 1.1 V
|   falling waveform, R_fixture 50.000, V_fixture 0.0: 20-80 % time 180ps typ, 266ps min, 123ps max; typ from 1.28 V to 0 V
[Pulldown]
|Voltage   I(typ)   I(min)   I(max)
-2.5V     -3.262A    -2.546A    -4.486A
-1.132V   -519.7mA   -519.8mA   -531.8mA
-1.056V   -384.7mA   -417.6mA   -351.2mA
-980mV    -261.1mA   -319.9mA   -205.2mA
-904mV    -157.6mA   -229mA     -128mA
-828mV    -87.78mA   -148.9mA   -106mA
-752mV    -59.6mA    -84.62mA   -88.61mA
-676mV    -45.95mA   -42.35mA   -70.41mA
-524mV    -25.94mA   -16.62mA   -39.48mA
844mV     24.87mA    16.01mA    38.07mA
3.2V      38.14mA    27.99mA    51.53mA
5V        115.8mA    81.78mA    177.2mA
[Pullup]
|Voltage   I(typ)   I(min)   I(max)
-2.5V     155.9mA    117.1mA    249.1mA
-548mV    22.75mA    17.28mA    35.69mA
60mV      -2.071mA   -1.49mA    -3.336mA
2.948V    -30.91mA   -24.9mA    -51.76mA
3.1V      -41.72mA   -69.76mA   -55.59mA
3.328V    -92.14mA   -296.5mA   -91.8mA
3.404V    -167.9mA   -392.9mA   -108.2mA
3.556V    -408.1mA   -598.7mA   -153.6mA
3.632V    -545.5mA   -705.6mA   -264.6mA
3.708V    -688.1mA   -814.1mA   -437.6mA
3.784V    -833.9mA   -923.9mA   -633.3mA
5V        -3.294A    -2.749A    -4.156A
[Ramp]
| variable   typ   min   max
dV/dt_r   0.770/0.368n   0.553/0.454n   1.066/0.227n
dV/dt_f   0.841/0.393n   0.579/0.463n   1.108/0.285n
R_load = 50.000
[Rising Waveform]
R_fixture= 50.000
V_fixture= 0.0
V_fixture_min= 0.0
V_fixture_max= 0.0
|time   V(typ)   V(min)   V(max)
0s        10.53nV    67.42nV    32.65nV
597ps     -252.8uV   6.153uV    -20.86mV
735ps     -630.2uV   6.153uV    870.1mV
809ps     -1.286mV   6.153uV    1.21V
1.045ns   -28.5mV    -361.5uV   1.593V
1.343ns   814mV      -985.2uV   1.698V
1.694ns   1.125V     -31.64mV   1.744V
2.248ns   1.227V     700.5mV    1.768V
2.992ns   1.267V     874.8mV    1.775V
20ns      1.283V     921.3mV    1.777V
[Rising Waveform]
R_fixture= 50.000
V_fixture= 2.500
V_fixture_min= 2.380
V_fixture_max= 2.630
|time   V(typ)   V(min)   V(max)
0s        1.099V     1.414V     783mV
544ps     1.099V     1.414V     796mV
592ps     1.099V     1.414V     1.026V
721ps     1.098V     1.414V     2.216V
899ps     1.092V     1.414V     2.516V
1.282ns   2.335V     1.414V     2.592V
1.517ns   2.432V     1.469V     2.608V
1.939ns   2.468V     2.237V     2.622V
2.392ns   2.485V     2.346V     2.627V
20ns      2.5V       2.38V      2.63V
[Falling Waveform]
R_fixture= 50.000
V_fixture= 2.500
V_fixture_min= 2.380
V_fixture_max= 2.630
|time   V(typ)   V(min)   V(max)
0s        2.5V       2.38V      2.63V
613ps     2.499V     2.38V      2.669V
832ps     2.5V       2.38V      1.476V
1.094ns   2.538V     2.379V     1.004V
1.344ns   1.725V     2.379V     878.2mV
1.699ns   1.305V     2.39V      816.4mV
1.901ns   1.229V     2.391V     804.3mV
2.423ns   1.149V     1.635V     789.2mV
3.529ns   1.108V     1.45V      783.3mV
20ns      1.099V     1.414V     783mV
[Falling Waveform]
R_fixture= 50.000
V_fixture= 0.0
V_fixture_min= 0.0
V_fixture_max= 0.0
|time   V(typ)   V(min)   V(max)
0s        1.283V     921.3mV    1.777V
579ps     1.282V     921.2mV    1.765V
710ps     1.282V     921.3mV    607.4mV
788ps     1.282V     921.2mV    250.5mV
1.024ns   1.24V      920.8mV    58.04mV
1.254ns   283.3mV    921mV      26.11mV
1.711ns   29.33mV    897.9mV    7.246mV
2.103ns   13.24mV    150.6mV    2.488mV
2.552ns   5.427mV    24.32mV    676.1uV
20ns      -65.56nV   22.28nV    74.4nV
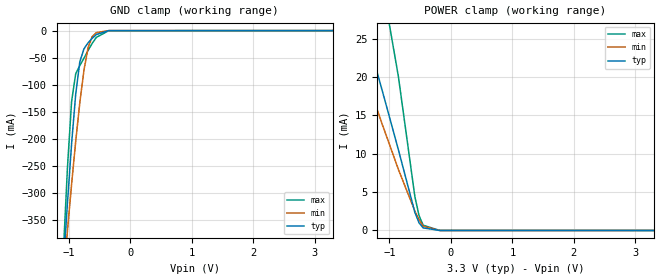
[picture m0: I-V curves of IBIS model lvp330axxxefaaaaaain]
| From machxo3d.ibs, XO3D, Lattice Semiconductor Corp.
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|   Model lvp330axxxefaaaaaain
[Model] lvp330axxxefaaaaaain
Model_type Input
Polarity   Non-Inverting
Enable   Active-High
Vinl =  1.840V
Vinh =  2.140V
C_comp   4.200pF   3.800pF   7.500pF
[Temperature Range]   25.000   0.105k   -40.000
[Voltage Range]   3.300V   3.140V   3.470V
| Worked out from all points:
|   GND clamp passes 1 mA (typ) near -0.43 V on its own axis
|   POWER clamp passes 1 mA (typ) near -0.52 V on its own axis
[GND_clamp]
|Voltage   I(typ)   I(min)   I(max)
-3.3V     -4.913A    -3.768A    -6.865A
-1.089V   -436.6mA   -458.9mA   -411.5mA
-1.022V   -318.8mA   -370mA     -253.2mA
-955mV    -210mA     -284.8mA   -131.4mA
-888mV    -117.9mA   -205.1mA   -80.02mA
-821mV    -57.76mA   -133.4mA   -64.74mA
-754mV    -33.88mA   -73.63mA   -51.23mA
-687mV    -22.76mA   -31.63mA   -36.92mA
-620mV    -14.21mA   -11.16mA   -23.73mA
-553mV    -7.411mA   -3.893mA   -12.67mA
-352mV    -131.3uA   -58.9uA    -219uA
3.3V      0A         0A         0A
[POWER_clamp]
|Voltage   I(typ)   I(min)   I(max)
-3.3V     82.87mA    74.06mA    118.1mA
-1.926V   41.79mA    34.09mA    64.67mA
-1.725V   35.77mA    28.77mA    56.95mA
-1.658V   33.78mA    27.04mA    54.31mA
-1.189V   20.27mA    15.49mA    35.28mA
-1.122V   18.35mA    13.94mA    32.42mA
-854mV    10.5mA     7.941mA    20.03mA
-586mV    2.349mA    2.531mA    4.384mA
-519mV    997.2uA    1.406mA    1.953mA
-452mV    344.2uA    549.2uA    685.9uA
-184mV    2.187uA    1.695uA    8.906uA
3.3V      0A         0A         0A
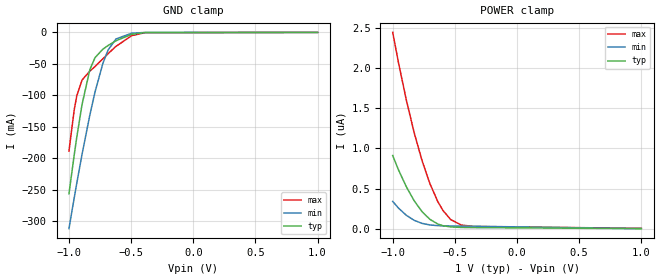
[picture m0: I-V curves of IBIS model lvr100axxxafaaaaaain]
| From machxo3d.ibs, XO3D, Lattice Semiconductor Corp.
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|   Model lvr100axxxafaaaaaain
[Model] lvr100axxxafaaaaaain
Model_type Input
Polarity   Non-Inverting
Enable   Active-High
Vinl =  0.350V
Vinh =  0.650V
C_comp   4.200pF   3.800pF   7.500pF
[Temperature Range]   25.000   0.105k   -40.000
[Voltage Range]   1.000V   0.950V   1.050V
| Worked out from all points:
|   GND clamp passes 1 mA (typ) near -0.44 V on its own axis
[GND_clamp]
|Voltage   I(typ)   I(min)   I(max)
-1V       -256.8mA   -312.3mA   -188.8mA
-958mV    -195.4mA   -263.6mA   -123.6mA
-937mV    -166.7mA   -239.9mA   -100.8mA
-895mV    -115mA     -194.3mA   -75.85mA
-832mV    -59.19mA   -131.5mA   -61.58mA
-790mV    -40.08mA   -94.52mA   -54.24mA
-727mV    -26.71mA   -49.22mA   -42.01mA
-685mV    -20.83mA   -27.95mA   -33.76mA
-622mV    -13.37mA   -10.52mA   -22.25mA
-496mV    -3.063mA   -1.311mA   -5.235mA
-391mV    -322.2uA   -138.3uA   -488uA
1V        0A         0A         0A
[POWER_clamp]
|Voltage   I(typ)   I(min)   I(max)
-1V       911.5nA    339.6nA    2.448uA
-953mV    731.7nA    255.7nA    2.066uA
-890mV    521.1nA    166.2nA    1.602uA
-827mV    347.4nA    103.7nA    1.195uA
-764mV    212.1nA    65.84nA    848.5nA
-701mV    116.4nA    46.42nA    562.7nA
-638mV    58.36nA    37.8nA     339.8nA
-596mV    36.88nA    35.03nA    227.4nA
-533mV    21.41nA    32.83nA    112.9nA
-449mV    15.14nA    31.27nA    45.35nA
-344mV    13.22nA    29.9nA     26.86nA
1V        0A         0A         4.09nA
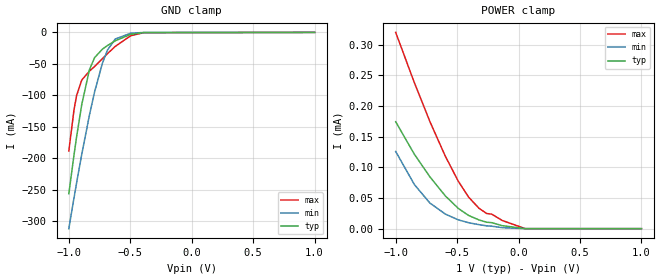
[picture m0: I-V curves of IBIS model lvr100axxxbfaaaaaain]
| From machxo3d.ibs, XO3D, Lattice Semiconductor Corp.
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|   Model lvr100axxxbfaaaaaain
[Model] lvr100axxxbfaaaaaain
Model_type Input
Polarity   Non-Inverting
Enable   Active-High
Vinl =  0.350V
Vinh =  0.650V
C_comp   4.200pF   3.800pF   7.500pF
[Temperature Range]   25.000   0.105k   -40.000
[Voltage Range]   1.000V   0.950V   1.050V
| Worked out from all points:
|   GND clamp passes 1 mA (typ) near -0.44 V on its own axis
[GND_clamp]
|Voltage   I(typ)   I(min)   I(max)
-1V       -256.8mA   -312.3mA   -188.8mA
-958mV    -195.4mA   -263.6mA   -123.6mA
-937mV    -166.7mA   -239.9mA   -100.8mA
-895mV    -115mA     -194.3mA   -75.86mA
-832mV    -59.2mA    -131.5mA   -61.59mA
-790mV    -40.08mA   -94.52mA   -54.25mA
-727mV    -26.71mA   -49.22mA   -42.01mA
-685mV    -20.83mA   -27.95mA   -33.77mA
-622mV    -13.37mA   -10.52mA   -22.26mA
-496mV    -3.067mA   -1.313mA   -5.244mA
-391mV    -327.5uA   -141.1uA   -499.4uA
1V        286.4pA    6.199nA    7.237nA
[POWER_clamp]
|Voltage   I(typ)   I(min)   I(max)
-1V       174.4uA    125.9uA    320.2uA
-848mV    121.4uA    71.97uA    238.1uA
-722mV    84.64uA    41.86uA    174.9uA
-596mV    53.44uA    23.77uA    118.1uA
-491mV    33.07uA    14.39uA    77.55uA
-407mV    21.58uA    9.722uA    51.54uA
-323mV    14.29uA    6.517uA    33.38uA
-260mV    10.51uA    4.612uA    24.74uA
-218mV    9.8uA      4.042uA    23.59uA
-134mV    4.908uA    1.626uA    13.42uA
55mV      0A         0A         0A
1V        0A         0A         0A
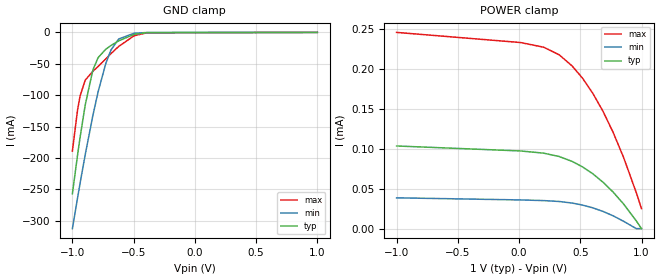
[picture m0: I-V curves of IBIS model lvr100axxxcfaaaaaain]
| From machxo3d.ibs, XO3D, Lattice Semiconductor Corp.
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|   Model lvr100axxxcfaaaaaain
[Model] lvr100axxxcfaaaaaain
Model_type Input
Polarity   Non-Inverting
Enable   Active-High
Vinl =  0.350V
Vinh =  0.650V
C_comp   4.200pF   3.800pF   7.500pF
[Temperature Range]   25.000   0.105k   -40.000
[Voltage Range]   1.000V   0.950V   1.050V
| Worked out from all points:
|   GND clamp passes 1 mA (typ) near -0.43 V on its own axis
[GND_clamp]
|Voltage   I(typ)   I(min)   I(max)
-1V       -256.8mA   -312.4mA   -188.8mA
-958mV    -195.4mA   -263.6mA   -123.6mA
-937mV    -166.8mA   -239.9mA   -100.9mA
-895mV    -115.1mA   -194.3mA   -75.93mA
-832mV    -59.24mA   -131.5mA   -61.67mA
-790mV    -40.13mA   -94.54mA   -54.33mA
-727mV    -26.76mA   -49.25mA   -42.08mA
-685mV    -20.89mA   -27.99mA   -33.84mA
-622mV    -13.43mA   -10.56mA   -22.34mA
-496mV    -3.137mA   -1.363mA   -5.351mA
-391mV    -399.3uA   -183.7uA   -613.7uA
1V        0A         0A         0A
[POWER_clamp]
|Voltage   I(typ)   I(min)   I(max)
-1V       103.6uA    38.63uA    245.9uA
13mV      97.35uA    35.99uA    233.2uA
202mV     94.59uA    35.16uA    227.3uA
328mV     90.37uA    34.04uA    217.8uA
433mV     84.31uA    32.11uA    203.9uA
517mV     77.53uA    29.6uA     188.8uA
601mV     68.91uA    26.14uA    169.9uA
685mV     58.29uA    21.65uA    147.2uA
769mV     45.7uA     16.04uA    120.4uA
853mV     31uA       9.286uA    89.53uA
958mV     9.559uA    0A         44.89uA
1V        0A         0A         25.08uA
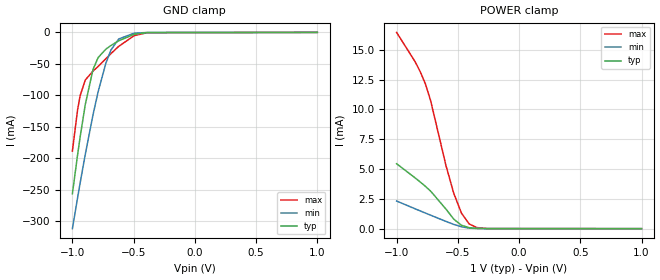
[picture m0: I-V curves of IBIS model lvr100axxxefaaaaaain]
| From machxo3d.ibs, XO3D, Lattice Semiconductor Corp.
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|   Model lvr100axxxefaaaaaain
[Model] lvr100axxxefaaaaaain
Model_type Input
Polarity   Non-Inverting
Enable   Active-High
Vinl =  0.350V
Vinh =  0.650V
C_comp   4.200pF   3.800pF   7.500pF
[Temperature Range]   25.000   0.105k   -40.000
[Voltage Range]   1.000V   0.950V   1.050V
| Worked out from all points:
|   GND clamp passes 1 mA (typ) near -0.44 V on its own axis
|   POWER clamp passes 1 mA (typ) near -0.55 V on its own axis
[GND_clamp]
|Voltage   I(typ)   I(min)   I(max)
-1V       -256.8mA   -312.3mA   -188.8mA
-958mV    -195.4mA   -263.6mA   -123.6mA
-937mV    -166.7mA   -239.9mA   -100.8mA
-895mV    -115mA     -194.3mA   -75.85mA
-832mV    -59.19mA   -131.5mA   -61.58mA
-790mV    -40.08mA   -94.52mA   -54.24mA
-727mV    -26.71mA   -49.22mA   -42.01mA
-685mV    -20.83mA   -27.95mA   -33.76mA
-622mV    -13.37mA   -10.52mA   -22.25mA
-496mV    -3.063mA   -1.311mA   -5.235mA
-391mV    -322.2uA   -138.3uA   -488uA
1V        0A         0A         0A
[POWER_clamp]
|Voltage   I(typ)   I(min)   I(max)
-1V       5.445mA    2.318mA    16.45mA
-848mV    4.249mA    1.661mA    13.98mA
-806mV    3.904mA    1.483mA    13.14mA
-764mV    3.54mA     1.306mA    12.11mA
-722mV    3.146mA    1.129mA    10.73mA
-596mV    1.632mA    604.1uA    5.258mA
-533mV    794uA      357.7uA    2.958mA
-470mV    280.6uA    155.9uA    1.295mA
-407mV    81.84uA    44.81uA    392.9uA
-344mV    22.5uA     10.67uA    89.57uA
-260mV    3.727uA    1.592uA    10.73uA
1V        0A         0A         4.09nA
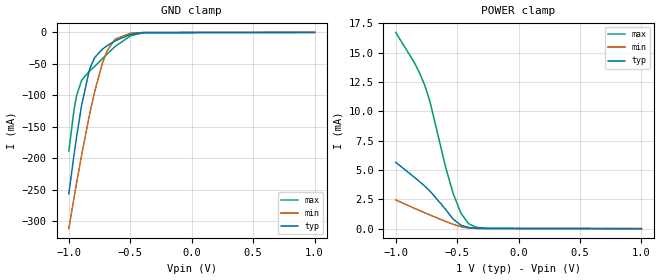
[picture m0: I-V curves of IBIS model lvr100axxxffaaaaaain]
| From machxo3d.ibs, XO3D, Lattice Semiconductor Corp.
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|   Model lvr100axxxffaaaaaain
[Model] lvr100axxxffaaaaaain
Model_type Input
Polarity   Non-Inverting
Enable   Active-High
Vinl =  0.350V
Vinh =  0.650V
C_comp   4.200pF   3.800pF   7.500pF
[Temperature Range]   25.000   0.105k   -40.000
[Voltage Range]   1.000V   0.950V   1.050V
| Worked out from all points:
|   GND clamp passes 1 mA (typ) near -0.44 V on its own axis
|   POWER clamp passes 1 mA (typ) near -0.55 V on its own axis
[GND_clamp]
|Voltage   I(typ)   I(min)   I(max)
-1V       -256.8mA   -312.3mA   -188.8mA
-958mV    -195.4mA   -263.6mA   -123.6mA
-937mV    -166.7mA   -239.9mA   -100.8mA
-895mV    -115mA     -194.3mA   -75.86mA
-832mV    -59.2mA    -131.5mA   -61.59mA
-790mV    -40.08mA   -94.52mA   -54.25mA
-727mV    -26.71mA   -49.22mA   -42.01mA
-685mV    -20.83mA   -27.95mA   -33.77mA
-622mV    -13.37mA   -10.52mA   -22.26mA
-496mV    -3.067mA   -1.313mA   -5.244mA
-391mV    -327.5uA   -141.1uA   -499.4uA
1V        286.7pA    6.201nA    7.237nA
[POWER_clamp]
|Voltage   I(typ)   I(min)   I(max)
-1V       5.662mA    2.455mA    16.74mA
-848mV    4.382mA    1.734mA    14.16mA
-806mV    4.016mA    1.544mA    13.29mA
-764mV    3.634mA    1.356mA    12.25mA
-722mV    3.224mA    1.17mA     10.87mA
-596mV    1.672mA    624.7uA    5.344mA
-533mV    820.7uA    372.4uA    3.015mA
-470mV    300.2uA    167uA      1.333mA
-407mV    98.91uA    53.74uA    422.4uA
-344mV    36.95uA    17.68uA    117.3uA
-260mV    14.09uA    6.17uA     34.25uA
1V        0A         0A         0A
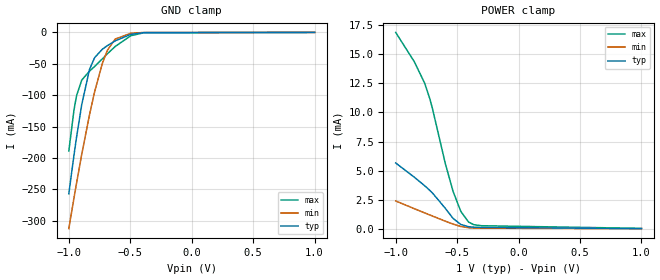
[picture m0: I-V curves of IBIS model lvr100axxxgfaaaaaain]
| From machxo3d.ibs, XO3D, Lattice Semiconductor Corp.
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|   Model lvr100axxxgfaaaaaain
[Model] lvr100axxxgfaaaaaain
Model_type Input
Polarity   Non-Inverting
Enable   Active-High
Vinl =  0.350V
Vinh =  0.650V
C_comp   4.200pF   3.800pF   7.500pF
[Temperature Range]   25.000   0.105k   -40.000
[Voltage Range]   1.000V   0.950V   1.050V
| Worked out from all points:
|   GND clamp passes 1 mA (typ) near -0.43 V on its own axis
|   POWER clamp passes 1 mA (typ) near -0.54 V on its own axis
[GND_clamp]
|Voltage   I(typ)   I(min)   I(max)
-1V       -256.8mA   -312.4mA   -188.8mA
-958mV    -195.4mA   -263.6mA   -123.6mA
-937mV    -166.8mA   -239.9mA   -100.9mA
-895mV    -115.1mA   -194.3mA   -75.93mA
-832mV    -59.24mA   -131.5mA   -61.67mA
-790mV    -40.13mA   -94.54mA   -54.33mA
-727mV    -26.76mA   -49.25mA   -42.08mA
-685mV    -20.89mA   -27.99mA   -33.84mA
-622mV    -13.43mA   -10.56mA   -22.34mA
-496mV    -3.137mA   -1.363mA   -5.351mA
-391mV    -399.3uA   -183.7uA   -613.7uA
1V        0A         0A         0A
[POWER_clamp]
|Voltage   I(typ)   I(min)   I(max)
-1V       5.654mA    2.384mA    16.89mA
-848mV    4.423mA    1.716mA    14.36mA
-764mV    3.693mA    1.355mA    12.51mA
-722mV    3.29mA     1.175mA    11.17mA
-701mV    3.073mA    1.085mA    10.34mA
-596mV    1.745mA    641uA      5.594mA
-533mV    882.2uA    391.9uA    3.206mA
-470mV    359.7uA    189.6uA    1.485mA
-407mV    167.7uA    79.78uA    569.9uA
-365mV    126.2uA    53.06uA    341.9uA
-302mV    105.9uA    40.56uA    252.6uA
1V        0A         0A         25.08uA
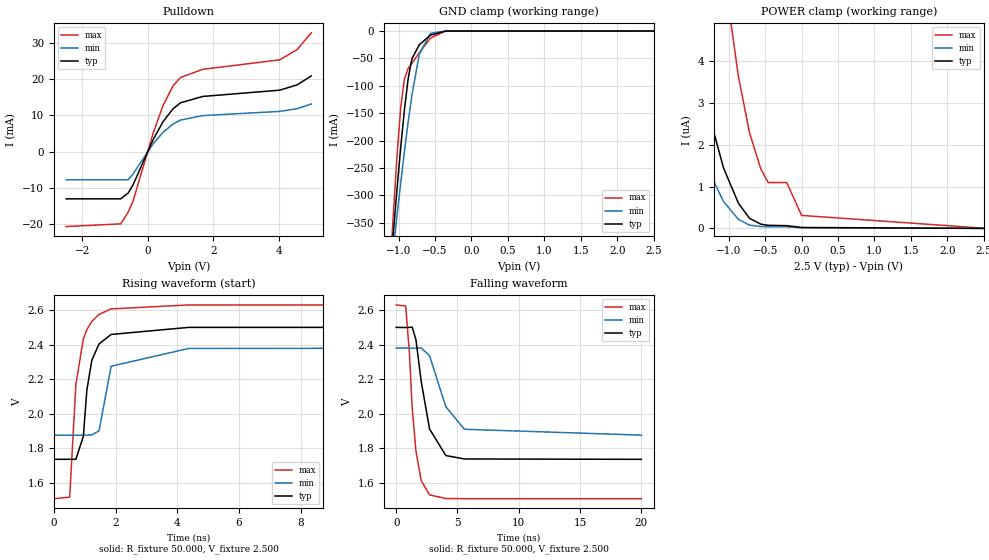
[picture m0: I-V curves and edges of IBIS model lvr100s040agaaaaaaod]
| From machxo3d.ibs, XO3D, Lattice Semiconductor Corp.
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|   Model lvr100s040agaaaaaaod
[Model] lvr100s040agaaaaaaod
Model_type I/O_open_drain
Polarity   Non-Inverting
Enable   Active-Low
Vinl =  0.350V
Vinh =  0.650V
Vmeas =  0.500V
Cref =  0.0F
Rref = 10.00k
Vref = 1.00V
C_comp   4.200pF   3.800pF   7.500pF
[Temperature Range]   25.000   0.105k   -40.000
[Voltage Range]   2.500V   2.380V   2.630V
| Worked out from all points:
|   slope of the pulldown table from 0 to 0.375 V, typ, clamps not added: 54.4 ohm
|   GND clamp passes 1 mA (typ) near -0.43 V on its own axis
|   rising waveform, R_fixture 50.000, V_fixture 2.500: 20-80 % time 333ps typ, 342ps min, 335ps max; typ from 1.74 V to 2.5 V
|   falling waveform, R_fixture 50.000, V_fixture 2.500: 20-80 % time 1.05ns typ, 1.58ns min, 702ps max; typ from 2.5 V to 1.74 V
[Pulldown]
|Voltage   I(typ)   I(min)   I(max)
-2.5V     -13.08mA   -7.815mA   -20.75mA
-828mV    -13.08mA   -7.815mA   -19.99mA
-600mV    -11.47mA   -7.815mA   -16.73mA
-448mV    -9.14mA    -6.165mA   -13.6mA
160mV     3.222mA    2.076mA    4.97mA
464mV     8.221mA    5.294mA    12.67mA
768mV     11.78mA    7.58mA     18.08mA
996mV     13.45mA    8.684mA    20.45mA
1.68V     15.22mA    9.932mA    22.72mA
4.036V    16.96mA    11.09mA    25.34mA
4.568V    18.42mA    11.84mA    28.18mA
5V        20.89mA    13.14mA    32.81mA
[GND_clamp]
|Voltage   I(typ)   I(min)   I(max)
-2.5V     -2.99A     -2.35A     -4.091A
-1.123V   -455.1mA   -463.2mA   -453.7mA
-1.072V   -370.5mA   -399.5mA   -336.3mA
-1.021V   -289.2mA   -337.4mA   -228.6mA
-970mV    -212.6mA   -277.3mA   -139.9mA
-919mV    -143.6mA   -220.1mA   -87.38mA
-868mV    -87.38mA   -166.5mA   -68.43mA
-817mV    -50.94mA   -117.8mA   -59.11mA
-715mV    -24.98mA   -42.37mA   -39.68mA
-562mV    -7.604mA   -4.134mA   -12.92mA
-358mV    -143.3uA   -63.27uA   -238.1uA
2.5V      0A         0A         0A
[POWER_clamp]
|Voltage   I(typ)   I(min)   I(max)
-2.5V     16.62uA    10.08uA    44.45uA
-2.09V    10.83uA    6.3uA      30.28uA
-1.682V   6.13uA     3.369uA    18.54uA
-1.376V   3.399uA    1.745uA    11.5uA
-1.07V    1.44uA     640.5nA    6.167uA
-866mV    600.8nA    214.7nA    3.625uA
-713mV    239.4nA    76.83nA    2.278uA
-560mV    101.4nA    44.89nA    1.428uA
-458mV    73.63nA    40.23nA    1.094uA
-203mV    64.98nA    37.72nA    1.094uA
1mV       21.5nA     15.07nA    309.5nA
2.5V      0A         0A         4.349nA
[Ramp]
| variable   typ   min   max
dV/dt_r   0.459/0.333n   0.303/0.339n   0.673/0.334n
dV/dt_f   0.459/1.056n   0.303/1.584n   0.673/0.696n
R_load = 50.000
[Rising Waveform]
R_fixture= 50.000
V_fixture= 2.500
V_fixture_min= 2.380
V_fixture_max= 2.630
|time   V(typ)   V(min)   V(max)
0s        1.736V     1.876V     1.508V
514ps     1.736V     1.876V     1.517V
715ps     1.736V     1.876V     2.169V
958ps     1.87V      1.876V     2.434V
1.071ns   2.137V     1.876V     2.487V
1.233ns   2.31V      1.877V     2.535V
1.466ns   2.404V     1.901V     2.575V
1.859ns   2.459V     2.275V     2.607V
4.372ns   2.5V       2.378V     2.63V
20ns      2.5V       2.38V      2.63V
[Falling Waveform]
R_fixture= 50.000
V_fixture= 2.500
V_fixture_min= 2.380
V_fixture_max= 2.630
|time   V(typ)   V(min)   V(max)
0s        2.5V       2.38V      2.63V
773ps     2.499V     2.38V      2.624V
1.083ns   2.5V       2.38V      2.347V
1.304ns   2.501V     2.379V     2.034V
1.61ns    2.429V     2.38V      1.784V
2.038ns   2.187V     2.381V     1.613V
2.72ns    1.912V     2.336V     1.53V
4.045ns   1.758V     2.041V     1.509V
5.562ns   1.738V     1.91V      1.508V
20ns      1.736V     1.876V     1.508V
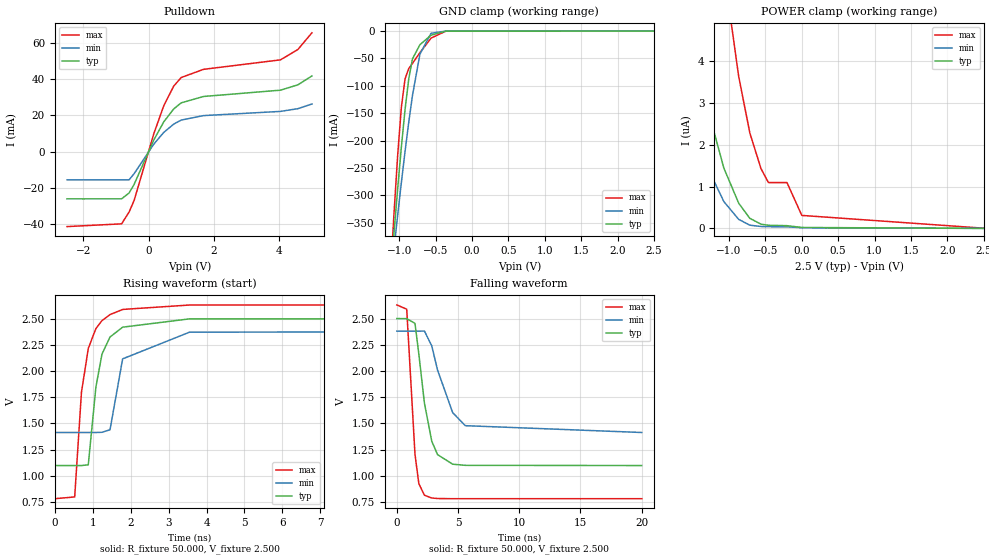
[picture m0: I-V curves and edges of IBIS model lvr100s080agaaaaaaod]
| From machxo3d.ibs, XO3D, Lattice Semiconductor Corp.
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|   Model lvr100s080agaaaaaaod
[Model] lvr100s080agaaaaaaod
Model_type I/O_open_drain
Polarity   Non-Inverting
Enable   Active-Low
Vinl =  0.350V
Vinh =  0.650V
Vmeas =  0.500V
Cref =  0.0F
Rref = 10.00k
Vref = 1.00V
C_comp   4.200pF   3.800pF   7.500pF
[Temperature Range]   25.000   0.105k   -40.000
[Voltage Range]   2.500V   2.380V   2.630V
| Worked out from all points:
|   slope of the pulldown table from 0 to 0.375 V, typ, clamps not added: 27.2 ohm
|   GND clamp passes 1 mA (typ) near -0.43 V on its own axis
|   rising waveform, R_fixture 50.000, V_fixture 2.500: 20-80 % time 327ps typ, 333ps min, 328ps max; typ from 1.1 V to 2.5 V
|   falling waveform, R_fixture 50.000, V_fixture 2.500: 20-80 % time 1ns typ, 1.58ns min, 547ps max; typ from 2.5 V to 1.1 V
[Pulldown]
|Voltage   I(typ)   I(min)   I(max)
-2.5V     -26.15mA   -15.63mA   -41.49mA
-828mV    -26.15mA   -15.63mA   -39.97mA
-600mV    -22.93mA   -15.63mA   -33.47mA
-448mV    -18.28mA   -12.33mA   -27.2mA
160mV     6.444mA    4.153mA    9.94mA
464mV     16.44mA    10.59mA    25.34mA
768mV     23.56mA    15.16mA    36.16mA
996mV     26.9mA     17.37mA    40.9mA
1.68V     30.43mA    19.86mA    45.43mA
4.036V    33.91mA    22.18mA    50.67mA
4.568V    36.84mA    23.68mA    56.35mA
5V        41.77mA    26.28mA    65.62mA
[GND_clamp]
|Voltage   I(typ)   I(min)   I(max)
-2.5V     -2.99A     -2.35A     -4.091A
-1.123V   -455.1mA   -463.2mA   -453.7mA
-1.072V   -370.5mA   -399.5mA   -336.3mA
-1.021V   -289.2mA   -337.4mA   -228.6mA
-970mV    -212.6mA   -277.3mA   -139.9mA
-919mV    -143.6mA   -220.1mA   -87.38mA
-868mV    -87.38mA   -166.5mA   -68.43mA
-817mV    -50.94mA   -117.8mA   -59.11mA
-715mV    -24.98mA   -42.37mA   -39.68mA
-562mV    -7.604mA   -4.134mA   -12.92mA
-358mV    -143.3uA   -63.27uA   -238.1uA
2.5V      0A         0A         0A
[POWER_clamp]
|Voltage   I(typ)   I(min)   I(max)
-2.5V     16.62uA    10.08uA    44.45uA
-2.09V    10.83uA    6.3uA      30.28uA
-1.682V   6.13uA     3.369uA    18.54uA
-1.376V   3.399uA    1.745uA    11.5uA
-1.07V    1.44uA     640.5nA    6.167uA
-866mV    600.8nA    214.6nA    3.625uA
-713mV    239.4nA    76.83nA    2.278uA
-560mV    101.4nA    44.89nA    1.428uA
-458mV    73.61nA    40.22nA    1.094uA
-203mV    64.97nA    37.72nA    1.094uA
1mV       21.5nA     15.07nA    309.5nA
2.5V      0A         0A         4.349nA
[Ramp]
| variable   typ   min   max
dV/dt_r   0.841/0.326n   0.579/0.333n   1.108/0.327n
dV/dt_f   0.841/0.997n   0.579/1.577n   1.108/0.547n
R_load = 50.000
[Rising Waveform]
R_fixture= 50.000
V_fixture= 2.500
V_fixture_min= 2.380
V_fixture_max= 2.630
|time   V(typ)   V(min)   V(max)
0s        1.099V     1.414V     783mV
525ps     1.099V     1.414V     799.8mV
703ps     1.099V     1.414V     1.796V
883ps     1.106V     1.414V     2.215V
1.084ns   1.847V     1.414V     2.405V
1.244ns   2.161V     1.416V     2.48V
1.456ns   2.324V     1.44V      2.538V
1.789ns   2.418V     2.116V     2.587V
3.55ns    2.497V     2.37V      2.629V
20ns      2.5V       2.38V      2.63V
[Falling Waveform]
R_fixture= 50.000
V_fixture= 2.500
V_fixture_min= 2.380
V_fixture_max= 2.630
|time   V(typ)   V(min)   V(max)
0s        2.5V       2.38V      2.63V
808ps     2.499V     2.38V      2.589V
1.484ns   2.454V     2.38V      1.205V
1.797ns   2.163V     2.38V      927.2mV
2.253ns   1.695V     2.381V     816mV
2.85ns    1.332V     2.241V     789.8mV
3.326ns   1.203V     2.009V     784.5mV
4.562ns   1.112V     1.603V     783.1mV
5.591ns   1.101V     1.479V     783mV
20ns      1.099V     1.414V     783mV
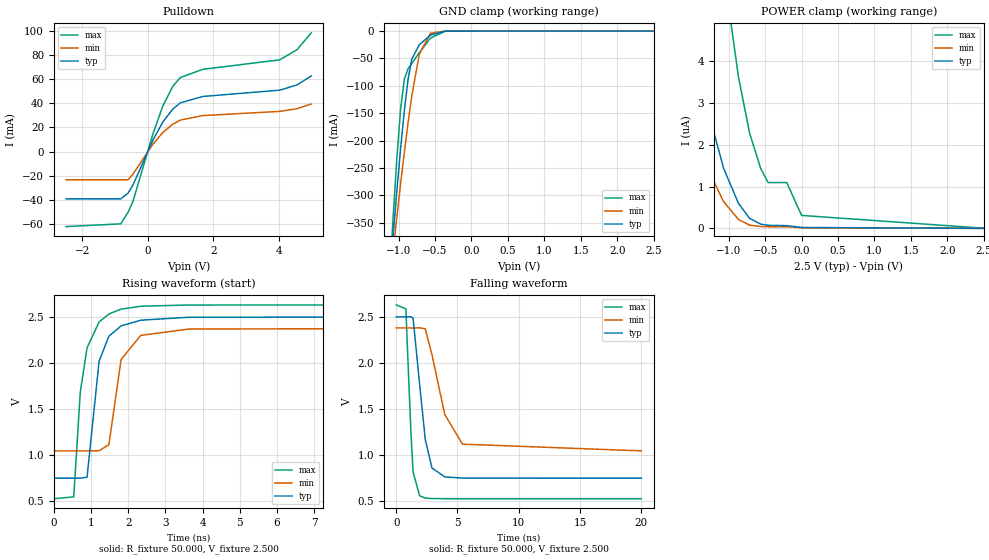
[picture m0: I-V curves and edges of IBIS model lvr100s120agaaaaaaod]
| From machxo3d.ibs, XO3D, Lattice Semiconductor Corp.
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|   Model lvr100s120agaaaaaaod
[Model] lvr100s120agaaaaaaod
Model_type I/O_open_drain
Polarity   Non-Inverting
Enable   Active-Low
Vinl =  0.350V
Vinh =  0.650V
Vmeas =  0.500V
Cref =  0.0F
Rref = 10.00k
Vref = 1.00V
C_comp   4.200pF   3.800pF   7.500pF
[Temperature Range]   25.000   0.105k   -40.000
[Voltage Range]   2.500V   2.380V   2.630V
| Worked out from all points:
|   slope of the pulldown table from 0 to 0.375 V, typ, clamps not added: 18.1 ohm
|   GND clamp passes 1 mA (typ) near -0.43 V on its own axis
|   rising waveform, R_fixture 50.000, V_fixture 2.500: 20-80 % time 324ps typ, 330ps min, 327ps max; typ from 0.747 V to 2.5 V
|   falling waveform, R_fixture 50.000, V_fixture 2.500: 20-80 % time 767ps typ, 1.43ns min, 383ps max; typ from 2.5 V to 0.747 V
[Pulldown]
|Voltage   I(typ)   I(min)   I(max)
-2.5V     -39.23mA   -23.44mA   -62.24mA
-828mV    -39.23mA   -23.44mA   -59.96mA
-600mV    -34.4mA    -23.44mA   -50.2mA
-448mV    -27.42mA   -18.49mA   -40.8mA
160mV     9.666mA    6.229mA    14.91mA
464mV     24.66mA    15.88mA    38.02mA
768mV     35.33mA    22.74mA    54.24mA
996mV     40.36mA    26.05mA    61.35mA
1.68V     45.65mA    29.8mA     68.15mA
4.036V    50.87mA    33.27mA    76.01mA
4.568V    55.25mA    35.53mA    84.53mA
5V        62.66mA    39.42mA    98.43mA
[GND_clamp]
|Voltage   I(typ)   I(min)   I(max)
-2.5V     -2.99A     -2.35A     -4.091A
-1.123V   -455.1mA   -463.2mA   -453.7mA
-1.072V   -370.5mA   -399.5mA   -336.3mA
-1.021V   -289.2mA   -337.4mA   -228.6mA
-970mV    -212.6mA   -277.3mA   -139.9mA
-919mV    -143.6mA   -220.1mA   -87.38mA
-868mV    -87.38mA   -166.5mA   -68.43mA
-817mV    -50.94mA   -117.8mA   -59.11mA
-715mV    -24.98mA   -42.37mA   -39.68mA
-562mV    -7.604mA   -4.134mA   -12.92mA
-358mV    -143.3uA   -63.27uA   -238.1uA
2.5V      0A         0A         0A
[POWER_clamp]
|Voltage   I(typ)   I(min)   I(max)
-2.5V     16.62uA    10.08uA    44.45uA
-2.09V    10.83uA    6.3uA      30.28uA
-1.682V   6.13uA     3.369uA    18.54uA
-1.376V   3.399uA    1.745uA    11.5uA
-1.07V    1.44uA     640.5nA    6.167uA
-866mV    600.8nA    214.6nA    3.625uA
-713mV    239.4nA    76.83nA    2.278uA
-560mV    101.4nA    44.88nA    1.428uA
-458mV    73.62nA    40.22nA    1.094uA
-203mV    64.97nA    37.72nA    1.094uA
1mV       21.5nA     15.07nA    309.5nA
2.5V      0A         0A         4.349nA
[Ramp]
| variable   typ   min   max
dV/dt_r   1.052/0.323n   0.801/0.328n   1.263/0.326n
dV/dt_f   1.052/0.770n   0.801/1.425n   1.263/0.383n
R_load = 50.000
[Rising Waveform]
R_fixture= 50.000
V_fixture= 2.500
V_fixture_min= 2.380
V_fixture_max= 2.630
|time   V(typ)   V(min)   V(max)
0s        747.2mV    1.044V     524.3mV
536ps     747.2mV    1.044V     544.1mV
712ps     747.6mV    1.044V     1.683V
894ps     757.4mV    1.044V     2.164V
1.218ns   2.019V     1.046V     2.445V
1.481ns   2.29V      1.111V     2.531V
1.81ns    2.402V     2.038V     2.584V
2.339ns   2.464V     2.299V     2.616V
3.627ns   2.496V     2.368V     2.629V
20ns      2.5V       2.38V      2.63V
[Falling Waveform]
R_fixture= 50.000
V_fixture= 2.500
V_fixture_min= 2.380
V_fixture_max= 2.630
|time   V(typ)   V(min)   V(max)
0s        2.5V       2.38V      2.63V
785ps     2.499V     2.38V      2.588V
1.199ns   2.502V     2.38V      1.247V
1.376ns   2.486V     2.379V     816mV
1.906ns   1.774V     2.381V     555.3mV
2.369ns   1.169V     2.371V     531.6mV
2.918ns   858mV      2.089V     525.9mV
3.962ns   761.3mV    1.44V      524.5mV
5.406ns   748.3mV    1.117V     524.3mV
20ns      747.1mV    1.044V     524.3mV
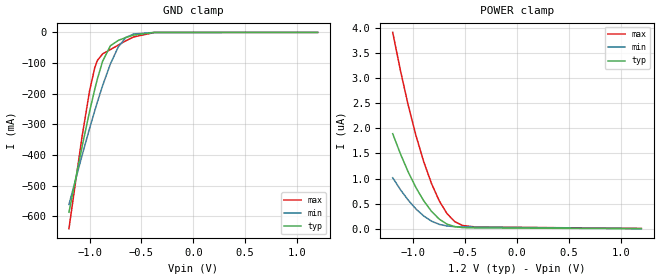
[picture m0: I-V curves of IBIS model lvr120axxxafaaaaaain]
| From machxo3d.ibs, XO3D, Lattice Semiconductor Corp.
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|   Model lvr120axxxafaaaaaain
[Model] lvr120axxxafaaaaaain
Model_type Input
Polarity   Non-Inverting
Enable   Active-High
Vinl =  0.420V
Vinh =  0.780V
C_comp   4.200pF   3.800pF   7.500pF
[Temperature Range]   25.000   0.105k   -40.000
[Voltage Range]   1.200V   1.140V   1.260V
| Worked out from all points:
|   GND clamp passes 1 mA (typ) near -0.44 V on its own axis
[GND_clamp]
|Voltage   I(typ)   I(min)   I(max)
-1.2V     -586.8mA   -561.6mA   -640.4mA
-1.075V   -375.3mA   -403.2mA   -342.9mA
-1V       -256.8mA   -312.3mA   -188.9mA
-950mV    -184.3mA   -254.5mA   -114.1mA
-925mV    -151.1mA   -226.6mA   -91.31mA
-875mV    -94.01mA   -173.6mA   -70.05mA
-800mV    -43.55mA   -102.9mA   -56.09mA
-725mV    -26.43mA   -48.04mA   -41.62mA
-650mV    -16.54mA   -16.37mA   -27.21mA
-575mV    -8.707mA   -5.042mA   -14.75mA
-375mV    -218.5uA   -94.95uA   -338.4uA
1.2V      0A         0A         0A
[POWER_clamp]
|Voltage   I(typ)   I(min)   I(max)
-1.2V     1.894uA    1.015uA    3.915uA
-1.125V   1.49uA     776.8nA    3.151uA
-1.05V    1.129uA    567.3nA    2.46uA
-975mV    816.5nA    391.5nA    1.853uA
-900mV    554.3nA    251.5nA    1.332uA
-825mV    344.1nA    149.5nA    897.5nA
-750mV    188.7nA    85.29nA    551.9nA
-675mV    89.22nA    52.64nA    298.2nA
-600mV    39.32nA    39.41nA    138.3nA
-525mV    21.15nA    34.59nA    62.94nA
-400mV    14.68nA    31.75nA    33.48nA
1.2V      0A         0A         4.359nA
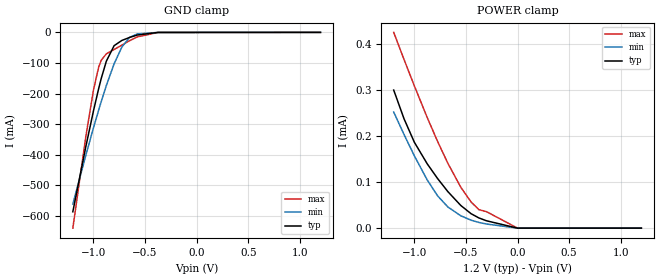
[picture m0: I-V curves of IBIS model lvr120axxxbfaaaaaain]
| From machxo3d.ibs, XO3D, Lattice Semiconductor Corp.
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|   Model lvr120axxxbfaaaaaain
[Model] lvr120axxxbfaaaaaain
Model_type Input
Polarity   Non-Inverting
Enable   Active-High
Vinl =  0.420V
Vinh =  0.780V
C_comp   4.200pF   3.800pF   7.500pF
[Temperature Range]   25.000   0.105k   -40.000
[Voltage Range]   1.200V   1.140V   1.260V
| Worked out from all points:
|   GND clamp passes 1 mA (typ) near -0.44 V on its own axis
[GND_clamp]
|Voltage   I(typ)   I(min)   I(max)
-1.2V     -586.8mA   -561.6mA   -640.4mA
-1.075V   -375.3mA   -403.2mA   -343mA
-1V       -256.8mA   -312.3mA   -188.9mA
-950mV    -184.3mA   -254.5mA   -114.1mA
-925mV    -151.1mA   -226.6mA   -91.32mA
-875mV    -94.02mA   -173.6mA   -70.06mA
-800mV    -43.55mA   -102.9mA   -56.1mA
-725mV    -26.44mA   -48.05mA   -41.64mA
-650mV    -16.54mA   -16.37mA   -27.23mA
-575mV    -8.714mA   -5.045mA   -14.76mA
-375mV    -228.6uA   -99.83uA   -361.9uA
1.2V      -40.6nA    0A         -5.328uA
[POWER_clamp]
|Voltage   I(typ)   I(min)   I(max)
-1.2V     299.6uA    251.9uA    424.8uA
-1.1V     237.3uA    203.2uA    366uA
-1V       186.4uA    156.9uA    308.7uA
-875mV    139.5uA    104.5uA    239.9uA
-775mV    107.7uA    70.19uA    188.3uA
-675mV    79.18uA    45.9uA     140.6uA
-550mV    49.19uA    26.84uA    88.83uA
-450mV    31.3uA     17.17uA    56.67uA
-375mV    22.16uA    12.38uA    40.12uA
-300mV    15.91uA    8.929uA    35.64uA
0V        5.946nA    9.945nA    0A
1.2V      0A         0A         0A
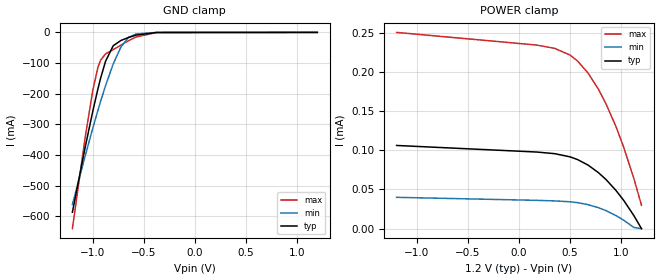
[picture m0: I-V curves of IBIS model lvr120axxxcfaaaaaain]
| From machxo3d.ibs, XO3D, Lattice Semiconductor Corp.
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|   Model lvr120axxxcfaaaaaain
[Model] lvr120axxxcfaaaaaain
Model_type Input
Polarity   Non-Inverting
Enable   Active-High
Vinl =  0.420V
Vinh =  0.780V
C_comp   4.200pF   3.800pF   7.500pF
[Temperature Range]   25.000   0.105k   -40.000
[Voltage Range]   1.200V   1.140V   1.260V
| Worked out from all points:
|   GND clamp passes 1 mA (typ) near -0.43 V on its own axis
[GND_clamp]
|Voltage   I(typ)   I(min)   I(max)
-1.2V     -586.8mA   -561.6mA   -640.5mA
-1.075V   -375.3mA   -403.2mA   -343mA
-1V       -256.9mA   -312.4mA   -188.9mA
-950mV    -184.4mA   -254.5mA   -114.2mA
-925mV    -151.2mA   -226.6mA   -91.32mA
-875mV    -94.06mA   -173.6mA   -70.11mA
-800mV    -43.6mA    -102.9mA   -56.16mA
-725mV    -26.48mA   -48.07mA   -41.7mA
-650mV    -16.59mA   -16.41mA   -27.29mA
-575mV    -8.769mA   -5.089mA   -14.84mA
-375mV    -291.8uA   -138.7uA   -456.3uA
1.2V      0A         0A         0A
[POWER_clamp]
|Voltage   I(typ)   I(min)   I(max)
-1.2V     106.1uA    39.97uA    250.3uA
175mV     97.71uA    36.09uA    234.1uA
350mV     95.62uA    35.39uA    229.9uA
500mV     91.59uA    34.27uA    221.4uA
575mV     88uA       33.12uA    213.6uA
675mV     81.17uA    30.65uA    198.6uA
775mV     71.72uA    26.88uA    178.5uA
850mV     62.93uA    23.1uA     159.7uA
950mV     48.73uA    16.7uA     130.1uA
1.025V    36.14uA    10.83uA    104uA
1.125V    16.67uA    1.54uA     64.01uA
1.2V      0A         0A         29.9uA
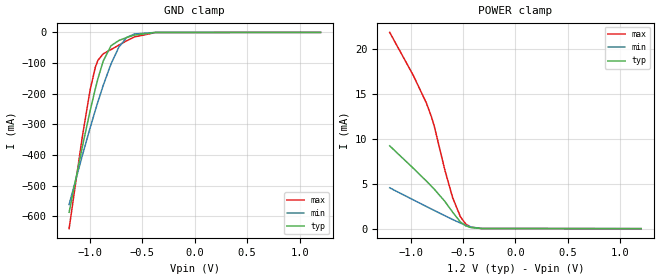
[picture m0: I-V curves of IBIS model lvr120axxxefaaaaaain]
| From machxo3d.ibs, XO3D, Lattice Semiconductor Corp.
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|   Model lvr120axxxefaaaaaain
[Model] lvr120axxxefaaaaaain
Model_type Input
Polarity   Non-Inverting
Enable   Active-High
Vinl =  0.420V
Vinh =  0.780V
C_comp   4.200pF   3.800pF   7.500pF
[Temperature Range]   25.000   0.105k   -40.000
[Voltage Range]   1.200V   1.140V   1.260V
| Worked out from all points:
|   GND clamp passes 1 mA (typ) near -0.44 V on its own axis
|   POWER clamp passes 1 mA (typ) near -0.55 V on its own axis
[GND_clamp]
|Voltage   I(typ)   I(min)   I(max)
-1.2V     -586.8mA   -561.6mA   -640.4mA
-1.075V   -375.3mA   -403.2mA   -342.9mA
-1V       -256.8mA   -312.3mA   -188.9mA
-950mV    -184.3mA   -254.5mA   -114.1mA
-925mV    -151.1mA   -226.6mA   -91.31mA
-875mV    -94.01mA   -173.6mA   -70.05mA
-800mV    -43.55mA   -102.9mA   -56.09mA
-725mV    -26.43mA   -48.04mA   -41.62mA
-650mV    -16.54mA   -16.37mA   -27.21mA
-575mV    -8.707mA   -5.042mA   -14.75mA
-375mV    -218.5uA   -94.95uA   -338.4uA
1.2V      0A         0A         0A
[POWER_clamp]
|Voltage   I(typ)   I(min)   I(max)
-1.2V     9.192mA    4.532mA    21.79mA
-975mV    6.705mA    3.198mA    17.01mA
-850mV    5.286mA    2.457mA    13.95mA
-800mV    4.693mA    2.165mA    12.36mA
-775mV    4.386mA    2.02mA     11.38mA
-675mV    3.045mA    1.445mA    6.565mA
-600mV    1.839mA    1.022mA    3.459mA
-525mV    735.1uA    619.3uA    1.314mA
-475mV    315uA      377.8uA    520.7uA
-425mV    119.9uA    184.6uA    168.5uA
-325mV    15.67uA    22.08uA    14.62uA
1.2V      0A         0A         4.359nA
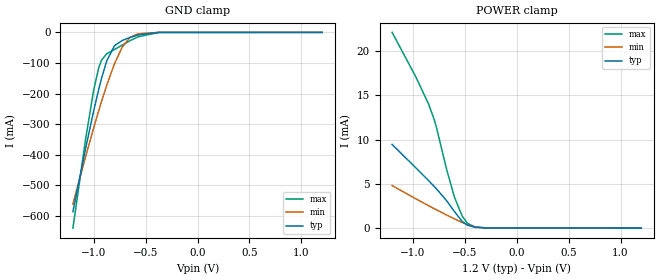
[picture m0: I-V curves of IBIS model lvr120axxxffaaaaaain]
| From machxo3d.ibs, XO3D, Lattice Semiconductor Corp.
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|   Model lvr120axxxffaaaaaain
[Model] lvr120axxxffaaaaaain
Model_type Input
Polarity   Non-Inverting
Enable   Active-High
Vinl =  0.420V
Vinh =  0.780V
C_comp   4.200pF   3.800pF   7.500pF
[Temperature Range]   25.000   0.105k   -40.000
[Voltage Range]   1.200V   1.140V   1.260V
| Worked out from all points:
|   GND clamp passes 1 mA (typ) near -0.44 V on its own axis
|   POWER clamp passes 1 mA (typ) near -0.54 V on its own axis
[GND_clamp]
|Voltage   I(typ)   I(min)   I(max)
-1.2V     -586.8mA   -561.6mA   -640.4mA
-1.075V   -375.3mA   -403.2mA   -343mA
-1V       -256.8mA   -312.3mA   -188.9mA
-950mV    -184.3mA   -254.5mA   -114.1mA
-925mV    -151.1mA   -226.6mA   -91.32mA
-875mV    -94.02mA   -173.6mA   -70.06mA
-800mV    -43.55mA   -102.9mA   -56.1mA
-725mV    -26.44mA   -48.05mA   -41.64mA
-650mV    -16.54mA   -16.37mA   -27.23mA
-575mV    -8.714mA   -5.045mA   -14.76mA
-375mV    -228.6uA   -99.83uA   -361.9uA
1.2V      -40.6nA    0A         -5.328uA
[POWER_clamp]
|Voltage   I(typ)   I(min)   I(max)
-1.2V     9.449mA    4.804mA    22.09mA
-975mV    6.851mA    3.332mA    17.15mA
-850mV    5.383mA    2.541mA    14.04mA
-800mV    4.773mA    2.233mA    12.45mA
-775mV    4.459mA    2.081mA    11.47mA
-675mV    3.094mA    1.484mA    6.639mA
-600mV    1.875mA    1.05mA     3.514mA
-525mV    761.2uA    638.6uA    1.354mA
-475mV    337.6uA    393.3uA    555.3uA
-400mV    92.8uA     128.2uA    126.5uA
-300mV    24.53uA    21.06uA    35.84uA
1.2V      0A         0A         0A
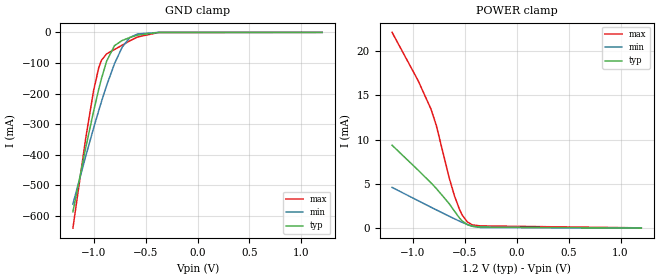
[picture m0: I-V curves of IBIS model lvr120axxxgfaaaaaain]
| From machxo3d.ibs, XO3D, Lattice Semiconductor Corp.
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|   Model lvr120axxxgfaaaaaain
[Model] lvr120axxxgfaaaaaain
Model_type Input
Polarity   Non-Inverting
Enable   Active-High
Vinl =  0.420V
Vinh =  0.780V
C_comp   4.200pF   3.800pF   7.500pF
[Temperature Range]   25.000   0.105k   -40.000
[Voltage Range]   1.200V   1.140V   1.260V
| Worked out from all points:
|   GND clamp passes 1 mA (typ) near -0.43 V on its own axis
|   POWER clamp passes 1 mA (typ) near -0.54 V on its own axis
[GND_clamp]
|Voltage   I(typ)   I(min)   I(max)
-1.2V     -586.8mA   -561.6mA   -640.5mA
-1.075V   -375.3mA   -403.2mA   -343mA
-1V       -256.9mA   -312.4mA   -188.9mA
-950mV    -184.4mA   -254.5mA   -114.2mA
-925mV    -151.2mA   -226.6mA   -91.32mA
-875mV    -94.06mA   -173.6mA   -70.11mA
-800mV    -43.6mA    -102.9mA   -56.16mA
-725mV    -26.48mA   -48.07mA   -41.7mA
-650mV    -16.59mA   -16.41mA   -27.29mA
-575mV    -8.769mA   -5.089mA   -14.84mA
-375mV    -291.8uA   -138.7uA   -456.3uA
1.2V      0A         0A         0A
[POWER_clamp]
|Voltage   I(typ)   I(min)   I(max)
-1.2V     9.366mA    4.602mA    22.12mA
-950mV    6.56mA     3.105mA    16.68mA
-825mV    5.108mA    2.36mA     13.44mA
-775mV    4.495mA    2.066mA    11.64mA
-650mV    2.76mA     1.342mA    5.68mA
-600mV    1.93mA     1.059mA    3.665mA
-550mV    1.131mA    784.8uA    2.086mA
-525mV    813.5uA    653.4uA    1.485mA
-475mV    392.6uA    411.1uA    691.4uA
-425mV    203.4uA    218.2uA    359.5uA
-350mV    120.1uA    74.59uA    252.4uA
1.2V      0A         0A         29.9uA
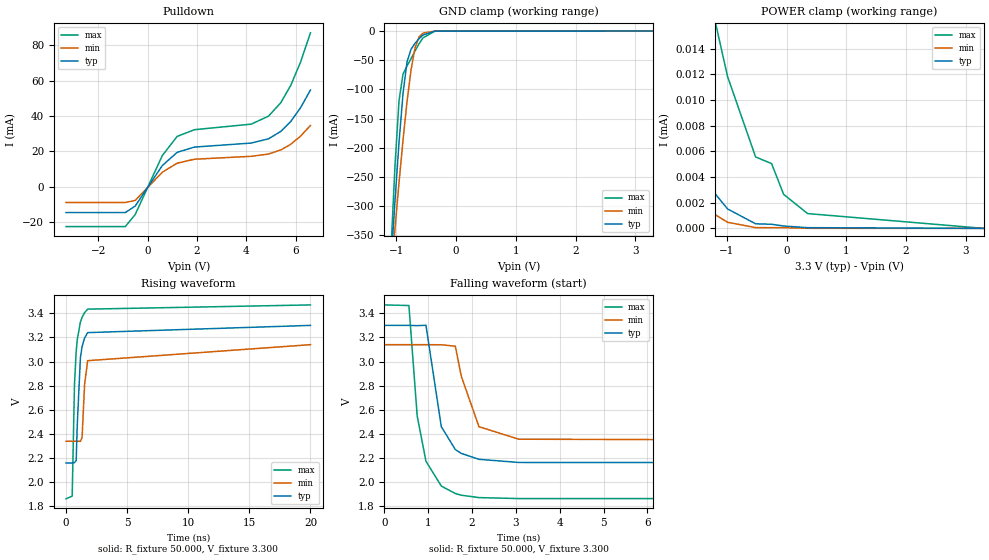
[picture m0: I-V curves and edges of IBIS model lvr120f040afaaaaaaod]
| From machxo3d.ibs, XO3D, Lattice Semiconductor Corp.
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|   Model lvr120f040afaaaaaaod
[Model] lvr120f040afaaaaaaod
Model_type I/O_open_drain
Polarity   Non-Inverting
Enable   Active-Low
Vinl =  0.420V
Vinh =  0.780V
Vmeas =  0.600V
Cref =  0.0F
Rref = 10.00k
Vref = 1.20V
C_comp   4.200pF   3.800pF   7.500pF
[Temperature Range]   25.000   0.105k   -40.000
[Voltage Range]   3.300V   3.140V   3.470V
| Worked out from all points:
|   slope of the pulldown table from 0 to 0.495 V, typ, clamps not added: 48.6 ohm
|   GND clamp passes 1 mA (typ) near -0.43 V on its own axis
|   rising waveform, R_fixture 50.000, V_fixture 3.300: 20-80 % time 324ps typ, 330ps min, 323ps max; typ from 2.16 V to 3.3 V
|   falling waveform, R_fixture 50.000, V_fixture 3.300: 20-80 % time 327ps typ, 367ps min, 315ps max; typ from 3.3 V to 2.16 V
[Pulldown]
|Voltage   I(typ)   I(min)   I(max)
-3.3V     -14.66mA   -8.951mA   -22.6mA
-900mV    -14.66mA   -8.951mA   -22.6mA
-500mV    -11.02mA   -7.807mA   -15.8mA
600mV     11.95mA    8.157mA    17.61mA
1.2V      19.4mA     13.27mA    28.41mA
1.9V      22.39mA    15.52mA    32.23mA
4.2V      24.66mA    17.16mA    35.37mA
4.9V      27.05mA    18.44mA    39.88mA
5.4V      31.26mA    20.77mA    47.51mA
5.8V      36.84mA    23.96mA    57.23mA
6.2V      44.67mA    28.59mA    70.48mA
6.6V      54.65mA    34.63mA    87.04mA
[GND_clamp]
|Voltage   I(typ)   I(min)   I(max)
-3.3V     -4.507A    -3.482A    -6.263A
-1.089V   -398.4mA   -420.6mA   -374.7mA
-1.022V   -290.7mA   -338.6mA   -230.6mA
-955mV    -191.4mA   -260.2mA   -120.1mA
-888mV    -107.5mA   -187mA     -73.69mA
-821mV    -53mA      -121.4mA   -59.83mA
-754mV    -31.41mA   -66.95mA   -47.44mA
-687mV    -21.17mA   -28.83mA   -34.23mA
-620mV    -13.21mA   -10.24mA   -21.98mA
-553mV    -6.877mA   -3.592mA   -11.71mA
-352mV    -122.8uA   -54.62uA   -209.3uA
3.3V      0A         0A         0A
[POWER_clamp]
|Voltage   I(typ)   I(min)   I(max)
-3.3V     530uA      347.3uA    956.2uA
-2.663V   63.57uA    15.44uA    254.2uA
-2.529V   27.42uA    10.98uA    148.7uA
-2.328V   15.78uA    8.532uA    64.82uA
-1.725V   7.398uA    3.713uA    31uA
-1.189V   2.659uA    1.053uA    15.99uA
-988mV    1.516uA    474.5nA    11.83uA
-519mV    357.5nA    63.29nA    5.567uA
-251mV    319nA      55.54nA    5.047uA
-50mV     187.6nA    55.54nA    2.655uA
352mV     56.19nA    7.349nA    1.154uA
3.3V      0A         0A         0A
[Ramp]
| variable   typ   min   max
dV/dt_r   0.685/0.325n   0.481/0.330n   0.965/0.323n
dV/dt_f   0.685/0.335n   0.481/0.363n   0.965/0.314n
R_load = 50.000
[Rising Waveform]
R_fixture= 50.000
V_fixture= 3.300
V_fixture_min= 3.140
V_fixture_max= 3.470
|time   V(typ)   V(min)   V(max)
0s        2.158V     2.338V     1.861V
502ps     2.158V     2.338V     1.882V
690ps     2.16V      2.338V     2.806V
829ps     2.178V     2.338V     3.082V
918ps     2.474V     2.338V     3.182V
1.176ns   3.033V     2.337V     3.328V
1.312ns   3.124V     2.369V     3.367V
1.518ns   3.195V     2.809V     3.406V
1.768ns   3.24V      3.007V     3.435V
20ns      3.3V       3.14V      3.47V
[Falling Waveform]
R_fixture= 50.000
V_fixture= 3.300
V_fixture_min= 3.140
V_fixture_max= 3.470
|time   V(typ)   V(min)   V(max)
0s        3.3V       3.14V      3.47V
560ps     3.3V       3.14V      3.465V
749ps     3.298V     3.14V      2.548V
949ps     3.301V     3.14V      2.172V
1.299ns   2.459V     3.139V     1.966V
1.619ns   2.269V     3.127V     1.904V
1.756ns   2.237V     2.877V     1.89V
2.158ns   2.188V     2.459V     1.87V
3.067ns   2.162V     2.355V     1.862V
20ns      2.158V     2.338V     1.861V
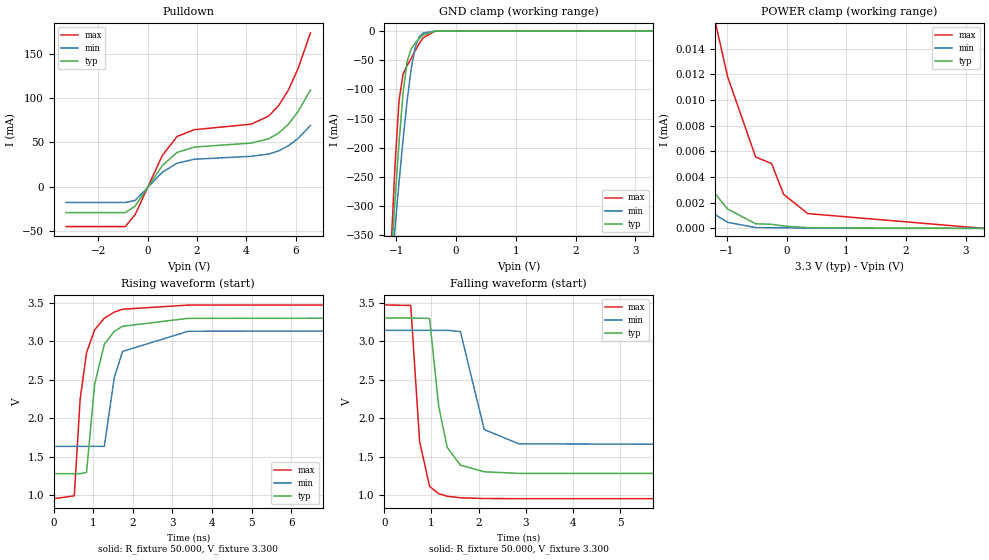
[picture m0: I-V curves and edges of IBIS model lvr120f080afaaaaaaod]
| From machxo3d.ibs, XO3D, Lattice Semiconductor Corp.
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|   Model lvr120f080afaaaaaaod
[Model] lvr120f080afaaaaaaod
Model_type I/O_open_drain
Polarity   Non-Inverting
Enable   Active-Low
Vinl =  0.420V
Vinh =  0.780V
Vmeas =  0.600V
Cref =  0.0F
Rref = 10.00k
Vref = 1.20V
C_comp   4.200pF   3.800pF   7.500pF
[Temperature Range]   25.000   0.105k   -40.000
[Voltage Range]   3.300V   3.140V   3.470V
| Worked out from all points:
|   slope of the pulldown table from 0 to 0.495 V, typ, clamps not added: 24.3 ohm
|   GND clamp passes 1 mA (typ) near -0.43 V on its own axis
|   rising waveform, R_fixture 50.000, V_fixture 3.300: 20-80 % time 316ps typ, 323ps min, 318ps max; typ from 1.28 V to 3.3 V
|   falling waveform, R_fixture 50.000, V_fixture 3.300: 20-80 % time 263ps typ, 329ps min, 183ps max; typ from 3.3 V to 1.28 V
[Pulldown]
|Voltage   I(typ)   I(min)   I(max)
-3.3V     -29.32mA   -17.9mA    -45.21mA
-900mV    -29.32mA   -17.9mA    -45.21mA
-500mV    -22.04mA   -15.61mA   -31.59mA
600mV     23.9mA     16.31mA    35.23mA
1.2V      38.8mA     26.54mA    56.81mA
1.9V      44.78mA    31.05mA    64.46mA
4.2V      49.32mA    34.33mA    70.73mA
4.9V      54.1mA     36.88mA    79.76mA
5.3V      60.39mA    40.34mA    91.21mA
5.7V      70.49mA    46.08mA    108.9mA
6.1V      84.99mA    54.58mA    133.7mA
6.6V      109.3mA    69.26mA    174.1mA
[GND_clamp]
|Voltage   I(typ)   I(min)   I(max)
-3.3V     -4.507A    -3.482A    -6.263A
-1.089V   -398.4mA   -420.6mA   -374.7mA
-1.022V   -290.7mA   -338.6mA   -230.6mA
-955mV    -191.4mA   -260.2mA   -120.1mA
-888mV    -107.5mA   -187mA     -73.69mA
-821mV    -53mA      -121.4mA   -59.83mA
-754mV    -31.41mA   -66.95mA   -47.44mA
-687mV    -21.17mA   -28.83mA   -34.23mA
-620mV    -13.21mA   -10.24mA   -21.98mA
-553mV    -6.877mA   -3.592mA   -11.71mA
-352mV    -122.8uA   -54.62uA   -209.3uA
3.3V      0A         0A         0A
[POWER_clamp]
|Voltage   I(typ)   I(min)   I(max)
-3.3V     530uA      347.3uA    956.2uA
-2.663V   63.57uA    15.44uA    254.2uA
-2.529V   27.42uA    10.98uA    148.7uA
-2.328V   15.78uA    8.532uA    64.82uA
-1.725V   7.398uA    3.713uA    31uA
-1.189V   2.659uA    1.053uA    15.99uA
-988mV    1.516uA    474.5nA    11.83uA
-519mV    357.5nA    63.28nA    5.567uA
-251mV    319nA      55.54nA    5.047uA
-50mV     187.6nA    55.54nA    2.655uA
352mV     56.19nA    7.349nA    1.154uA
3.3V      0A         0A         0A
[Ramp]
| variable   typ   min   max
dV/dt_r   1.213/0.316n   0.904/0.321n   1.510/0.316n
dV/dt_f   1.213/0.263n   0.904/0.329n   1.510/0.183n
R_load = 50.000
[Rising Waveform]
R_fixture= 50.000
V_fixture= 3.300
V_fixture_min= 3.140
V_fixture_max= 3.470
|time   V(typ)   V(min)   V(max)
0s        1.278V     1.633V     953.3mV
517ps     1.278V     1.633V     990.3mV
665ps     1.279V     1.633V     2.243V
827ps     1.294V     1.633V     2.849V
1.032ns   2.437V     1.634V     3.147V
1.277ns   2.96V      1.633V     3.298V
1.529ns   3.126V     2.526V     3.377V
1.738ns   3.192V     2.866V     3.414V
3.399ns   3.296V     3.128V     3.468V
20ns      3.3V       3.14V      3.47V
[Falling Waveform]
R_fixture= 50.000
V_fixture= 3.300
V_fixture_min= 3.140
V_fixture_max= 3.470
|time   V(typ)   V(min)   V(max)
0s        3.3V       3.14V      3.47V
560ps     3.3V       3.14V      3.463V
748ps     3.298V     3.14V      1.695V
960ps     3.294V     3.14V      1.113V
1.152ns   2.157V     3.139V     1.018V
1.333ns   1.621V     3.14V      984.9mV
1.613ns   1.389V     3.125V     965.4mV
2.12ns    1.303V     1.851V     955.4mV
2.853ns   1.282V     1.666V     953.5mV
20ns      1.278V     1.633V     953.2mV
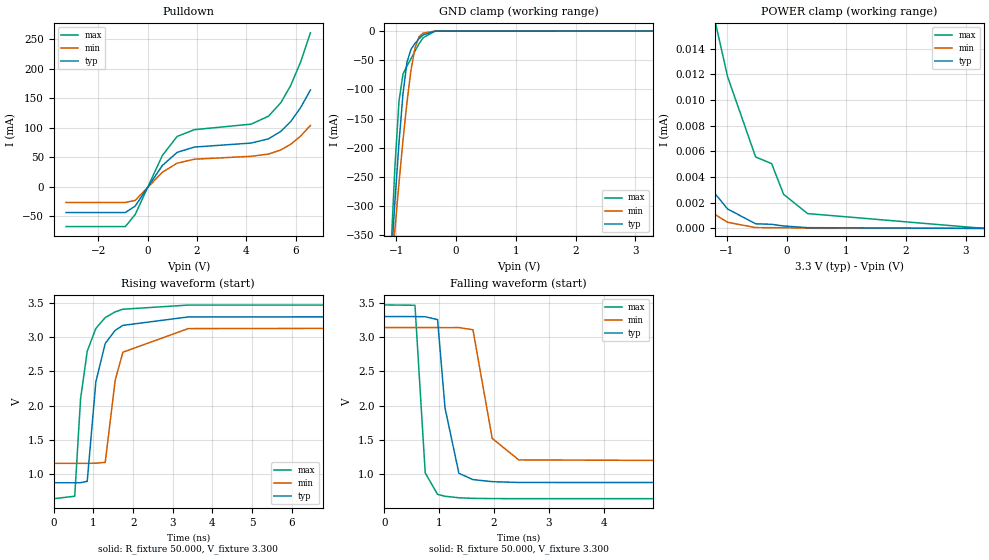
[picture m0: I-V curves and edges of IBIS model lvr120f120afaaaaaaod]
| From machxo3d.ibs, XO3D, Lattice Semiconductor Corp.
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|   Model lvr120f120afaaaaaaod
[Model] lvr120f120afaaaaaaod
Model_type I/O_open_drain
Polarity   Non-Inverting
Enable   Active-Low
Vinl =  0.420V
Vinh =  0.780V
Vmeas =  0.600V
Cref =  0.0F
Rref = 10.00k
Vref = 1.20V
C_comp   4.200pF   3.800pF   7.500pF
[Temperature Range]   25.000   0.105k   -40.000
[Voltage Range]   3.300V   3.140V   3.470V
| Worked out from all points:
|   slope of the pulldown table from 0 to 0.495 V, typ, clamps not added: 16.2 ohm
|   GND clamp passes 1 mA (typ) near -0.43 V on its own axis
|   rising waveform, R_fixture 50.000, V_fixture 3.300: 20-80 % time 311ps typ, 318ps min, 315ps max; typ from 0.878 V to 3.3 V
|   falling waveform, R_fixture 50.000, V_fixture 3.300: 20-80 % time 176ps typ, 260ps min, 115ps max; typ from 3.3 V to 0.878 V
[Pulldown]
|Voltage   I(typ)   I(min)   I(max)
-3.3V     -43.98mA   -26.85mA   -67.81mA
-900mV    -43.98mA   -26.85mA   -67.81mA
-500mV    -33.06mA   -23.42mA   -47.39mA
600mV     35.86mA    24.47mA    52.84mA
1.2V      58.2mA     39.81mA    85.22mA
1.9V      67.18mA    46.57mA    96.69mA
4.2V      73.98mA    51.49mA    106.1mA
4.9V      81.14mA    55.32mA    119.6mA
5.4V      93.79mA    62.3mA     142.5mA
5.8V      110.5mA    71.89mA    171.7mA
6.2V      134mA      85.76mA    211.4mA
6.6V      164mA      103.9mA    261.1mA
[GND_clamp]
|Voltage   I(typ)   I(min)   I(max)
-3.3V     -4.507A    -3.482A    -6.263A
-1.089V   -398.4mA   -420.6mA   -374.7mA
-1.022V   -290.7mA   -338.6mA   -230.6mA
-955mV    -191.4mA   -260.2mA   -120.1mA
-888mV    -107.5mA   -187mA     -73.69mA
-821mV    -53mA      -121.4mA   -59.83mA
-754mV    -31.41mA   -66.95mA   -47.44mA
-687mV    -21.17mA   -28.83mA   -34.23mA
-620mV    -13.21mA   -10.24mA   -21.98mA
-553mV    -6.877mA   -3.592mA   -11.71mA
-352mV    -122.8uA   -54.62uA   -209.3uA
3.3V      0A         0A         0A
[POWER_clamp]
|Voltage   I(typ)   I(min)   I(max)
-3.3V     530uA      347.3uA    956.2uA
-2.663V   63.57uA    15.44uA    254.2uA
-2.529V   27.42uA    10.98uA    148.7uA
-2.328V   15.78uA    8.532uA    64.82uA
-1.725V   7.398uA    3.713uA    31uA
-1.189V   2.659uA    1.053uA    15.99uA
-988mV    1.516uA    474.5nA    11.83uA
-519mV    357.5nA    63.28nA    5.567uA
-251mV    319nA      55.54nA    5.047uA
-50mV     187.6nA    55.54nA    2.655uA
352mV     56.19nA    7.349nA    1.154uA
3.3V      0A         0A         0A
[Ramp]
| variable   typ   min   max
dV/dt_r   1.453/0.314n   1.187/0.316n   1.694/0.315n
dV/dt_f   1.453/0.175n   1.187/0.259n   1.694/0.114n
R_load = 50.000
[Rising Waveform]
R_fixture= 50.000
V_fixture= 3.300
V_fixture_min= 3.140
V_fixture_max= 3.470
|time   V(typ)   V(min)   V(max)
0s        878.1mV    1.161V     645.8mV
527ps     878.1mV    1.161V     681.6mV
674ps     879mV      1.161V     2.1V
842ps     898.9mV    1.161V     2.794V
1.06ns    2.35V      1.163V     3.128V
1.296ns   2.909V     1.175V     3.286V
1.548ns   3.1V       2.376V     3.369V
1.742ns   3.172V     2.781V     3.407V
3.389ns   3.295V     3.125V     3.468V
20ns      3.3V       3.14V      3.47V
[Falling Waveform]
R_fixture= 50.000
V_fixture= 3.300
V_fixture_min= 3.140
V_fixture_max= 3.470
|time   V(typ)   V(min)   V(max)
0s        3.3V       3.14V      3.47V
558ps     3.3V       3.14V      3.465V
745ps     3.298V     3.14V      1.021V
970ps     3.256V     3.14V      708.8mV
1.106ns   1.968V     3.139V     681.6mV
1.359ns   1.016V     3.14V      659.3mV
1.615ns   924.1mV    3.108V     650.9mV
1.966ns   894.1mV    1.525V     647.3mV
2.451ns   882.2mV    1.211V     646.2mV
20ns      878.1mV    1.161V     645.8mV
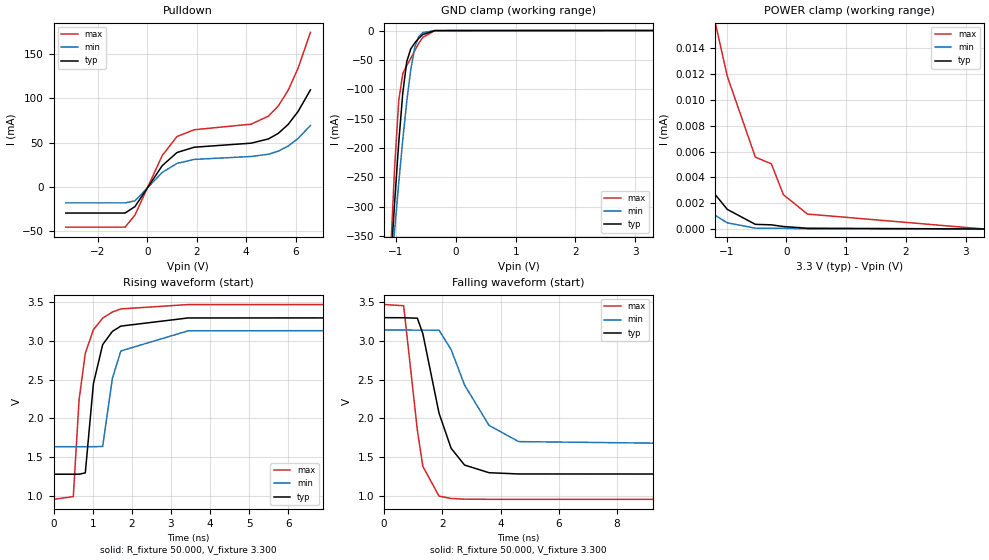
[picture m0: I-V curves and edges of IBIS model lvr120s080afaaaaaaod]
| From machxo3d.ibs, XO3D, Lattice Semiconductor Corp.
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|   Model lvr120s080afaaaaaaod
[Model] lvr120s080afaaaaaaod
Model_type I/O_open_drain
Polarity   Non-Inverting
Enable   Active-Low
Vinl =  0.420V
Vinh =  0.780V
Vmeas =  0.600V
Cref =  0.0F
Rref = 10.00k
Vref = 1.20V
C_comp   4.200pF   3.800pF   7.500pF
[Temperature Range]   25.000   0.105k   -40.000
[Voltage Range]   3.300V   3.140V   3.470V
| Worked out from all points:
|   slope of the pulldown table from 0 to 0.495 V, typ, clamps not added: 24.3 ohm
|   GND clamp passes 1 mA (typ) near -0.43 V on its own axis
|   rising waveform, R_fixture 50.000, V_fixture 3.300: 20-80 % time 317ps typ, 322ps min, 317ps max; typ from 1.28 V to 3.3 V
|   falling waveform, R_fixture 50.000, V_fixture 3.300: 20-80 % time 779ps typ, 1.19ns min, 449ps max; typ from 3.3 V to 1.28 V
[Pulldown]
|Voltage   I(typ)   I(min)   I(max)
-3.3V     -29.32mA   -17.9mA    -45.21mA
-900mV    -29.32mA   -17.9mA    -45.21mA
-500mV    -22.04mA   -15.61mA   -31.59mA
600mV     23.9mA     16.31mA    35.23mA
1.2V      38.8mA     26.54mA    56.81mA
1.9V      44.78mA    31.05mA    64.46mA
4.2V      49.32mA    34.33mA    70.73mA
4.9V      54.1mA     36.88mA    79.76mA
5.3V      60.39mA    40.34mA    91.21mA
5.7V      70.49mA    46.08mA    108.9mA
6.1V      84.99mA    54.58mA    133.7mA
6.6V      109.3mA    69.26mA    174.1mA
[GND_clamp]
|Voltage   I(typ)   I(min)   I(max)
-3.3V     -4.507A    -3.482A    -6.263A
-1.089V   -398.4mA   -420.6mA   -374.7mA
-1.022V   -290.7mA   -338.6mA   -230.6mA
-955mV    -191.4mA   -260.2mA   -120.1mA
-888mV    -107.5mA   -187mA     -73.69mA
-821mV    -53mA      -121.4mA   -59.83mA
-754mV    -31.41mA   -66.95mA   -47.44mA
-687mV    -21.17mA   -28.83mA   -34.23mA
-620mV    -13.21mA   -10.24mA   -21.98mA
-553mV    -6.877mA   -3.592mA   -11.71mA
-352mV    -122.8uA   -54.62uA   -209.3uA
3.3V      0A         0A         0A
[POWER_clamp]
|Voltage   I(typ)   I(min)   I(max)
-3.3V     530uA      347.3uA    956.2uA
-2.663V   63.57uA    15.44uA    254.2uA
-2.529V   27.42uA    10.98uA    148.7uA
-2.328V   15.78uA    8.532uA    64.82uA
-1.725V   7.398uA    3.714uA    31uA
-1.189V   2.659uA    1.053uA    15.99uA
-988mV    1.516uA    474.5nA    11.83uA
-519mV    357.5nA    63.32nA    5.567uA
-251mV    319nA      55.57nA    5.047uA
-50mV     187.6nA    55.57nA    2.655uA
352mV     56.19nA    7.349nA    1.154uA
3.3V      0A         0A         0A
[Ramp]
| variable   typ   min   max
dV/dt_r   1.213/0.316n   0.904/0.321n   1.510/0.316n
dV/dt_f   1.213/0.780n   0.904/1.190n   1.510/0.448n
R_load = 50.000
[Rising Waveform]
R_fixture= 50.000
V_fixture= 3.300
V_fixture_min= 3.140
V_fixture_max= 3.470
|time   V(typ)   V(min)   V(max)
0s        1.278V     1.633V     953.3mV
505ps     1.278V     1.633V     988.4mV
653ps     1.278V     1.633V     2.239V
812ps     1.295V     1.633V     2.84V
1.019ns   2.447V     1.633V     3.145V
1.256ns   2.952V     1.636V     3.294V
1.505ns   3.123V     2.518V     3.373V
1.721ns   3.191V     2.87V      3.413V
3.439ns   3.296V     3.13V      3.469V
20ns      3.3V       3.14V      3.47V
[Falling Waveform]
R_fixture= 50.000
V_fixture= 3.300
V_fixture_min= 3.140
V_fixture_max= 3.470
|time   V(typ)   V(min)   V(max)
0s        3.3V       3.14V      3.47V
673ps     3.299V     3.14V      3.454V
1.144ns   3.293V     3.139V     1.844V
1.333ns   3.092V     3.139V     1.378V
1.888ns   2.066V     3.138V     994.7mV
2.303ns   1.613V     2.888V     964.3mV
2.765ns   1.396V     2.43V      955.6mV
3.607ns   1.297V     1.908V     953.4mV
4.623ns   1.281V     1.699V     953.2mV
20ns      1.278V     1.633V     953.2mV
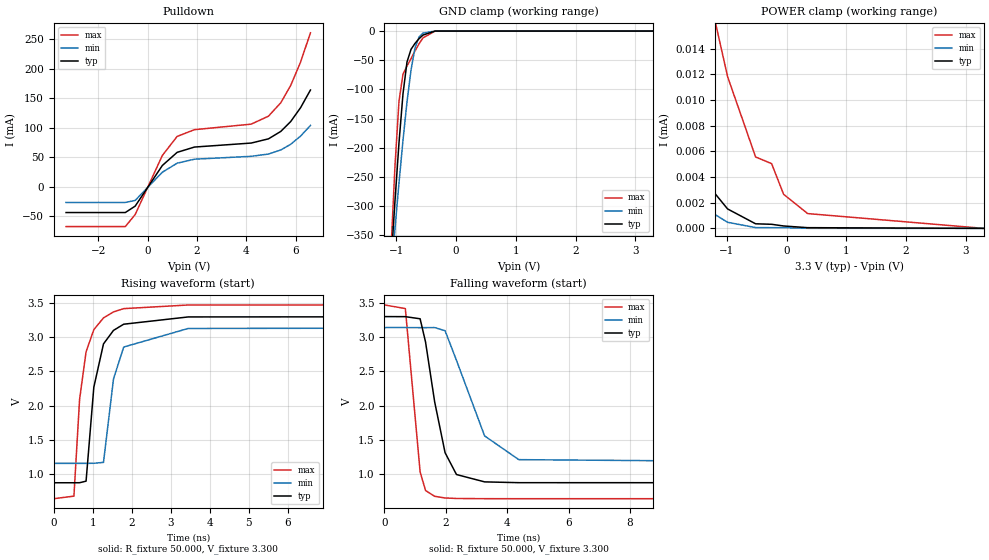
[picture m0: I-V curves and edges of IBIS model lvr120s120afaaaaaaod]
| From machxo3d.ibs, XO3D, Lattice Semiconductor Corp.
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|   Model lvr120s120afaaaaaaod
[Model] lvr120s120afaaaaaaod
Model_type I/O_open_drain
Polarity   Non-Inverting
Enable   Active-Low
Vinl =  0.420V
Vinh =  0.780V
Vmeas =  0.600V
Cref =  0.0F
Rref = 10.00k
Vref = 1.20V
C_comp   4.200pF   3.800pF   7.500pF
[Temperature Range]   25.000   0.105k   -40.000
[Voltage Range]   3.300V   3.140V   3.470V
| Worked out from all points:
|   slope of the pulldown table from 0 to 0.495 V, typ, clamps not added: 16.2 ohm
|   GND clamp passes 1 mA (typ) near -0.43 V on its own axis
|   rising waveform, R_fixture 50.000, V_fixture 3.300: 20-80 % time 311ps typ, 318ps min, 316ps max; typ from 0.878 V to 3.3 V
|   falling waveform, R_fixture 50.000, V_fixture 3.300: 20-80 % time 568ps typ, 982ps min, 311ps max; typ from 3.3 V to 0.878 V
[Pulldown]
|Voltage   I(typ)   I(min)   I(max)
-3.3V     -43.98mA   -26.85mA   -67.81mA
-900mV    -43.98mA   -26.85mA   -67.81mA
-500mV    -33.06mA   -23.42mA   -47.39mA
600mV     35.86mA    24.47mA    52.84mA
1.2V      58.2mA     39.81mA    85.22mA
1.9V      67.18mA    46.57mA    96.69mA
4.2V      73.98mA    51.49mA    106.1mA
4.9V      81.14mA    55.32mA    119.6mA
5.4V      93.79mA    62.3mA     142.5mA
5.8V      110.5mA    71.89mA    171.7mA
6.2V      134mA      85.76mA    211.4mA
6.6V      164mA      103.9mA    261.1mA
[GND_clamp]
|Voltage   I(typ)   I(min)   I(max)
-3.3V     -4.507A    -3.482A    -6.263A
-1.089V   -398.4mA   -420.6mA   -374.7mA
-1.022V   -290.7mA   -338.6mA   -230.6mA
-955mV    -191.4mA   -260.2mA   -120.1mA
-888mV    -107.5mA   -187mA     -73.69mA
-821mV    -53mA      -121.4mA   -59.83mA
-754mV    -31.41mA   -66.95mA   -47.44mA
-687mV    -21.17mA   -28.83mA   -34.23mA
-620mV    -13.21mA   -10.24mA   -21.98mA
-553mV    -6.877mA   -3.592mA   -11.71mA
-352mV    -122.8uA   -54.62uA   -209.3uA
3.3V      0A         0A         0A
[POWER_clamp]
|Voltage   I(typ)   I(min)   I(max)
-3.3V     530uA      347.3uA    956.2uA
-2.663V   63.57uA    15.44uA    254.2uA
-2.529V   27.42uA    10.98uA    148.7uA
-2.328V   15.78uA    8.532uA    64.82uA
-1.725V   7.398uA    3.714uA    31uA
-1.189V   2.659uA    1.053uA    15.99uA
-988mV    1.516uA    474.5nA    11.83uA
-519mV    357.5nA    63.32nA    5.567uA
-251mV    319nA      55.57nA    5.047uA
-50mV     187.6nA    55.57nA    2.655uA
352mV     56.19nA    7.349nA    1.154uA
3.3V      0A         0A         0A
[Ramp]
| variable   typ   min   max
dV/dt_r   1.453/0.314n   1.187/0.316n   1.694/0.315n
dV/dt_f   1.453/0.568n   1.187/0.986n   1.694/0.311n
R_load = 50.000
[Rising Waveform]
R_fixture= 50.000
V_fixture= 3.300
V_fixture_min= 3.140
V_fixture_max= 3.470
|time   V(typ)   V(min)   V(max)
0s        878.1mV    1.161V     645.8mV
516ps     878.1mV    1.161V     683.2mV
662ps     878.6mV    1.161V     2.096V
828ps     901.5mV    1.161V     2.787V
1.027ns   2.271V     1.162V     3.109V
1.275ns   2.902V     1.175V     3.281V
1.532ns   3.099V     2.392V     3.368V
1.794ns   3.189V     2.856V     3.416V
3.451ns   3.295V     3.127V     3.469V
20ns      3.3V       3.14V      3.47V
[Falling Waveform]
R_fixture= 50.000
V_fixture= 3.300
V_fixture_min= 3.140
V_fixture_max= 3.470
|time   V(typ)   V(min)   V(max)
0s        3.3V       3.14V      3.47V
683ps     3.299V     3.14V      3.417V
1.164ns   3.268V     3.139V     1.037V
1.341ns   2.929V     3.139V     765.2mV
1.637ns   2.059V     3.14V      680.7mV
1.977ns   1.316V     3.094V     656.6mV
2.348ns   997.9mV    2.662V     648.9mV
3.264ns   890.9mV    1.561V     646mV
4.377ns   879.3mV    1.215V     645.8mV
20ns      878mV      1.161V     645.8mV
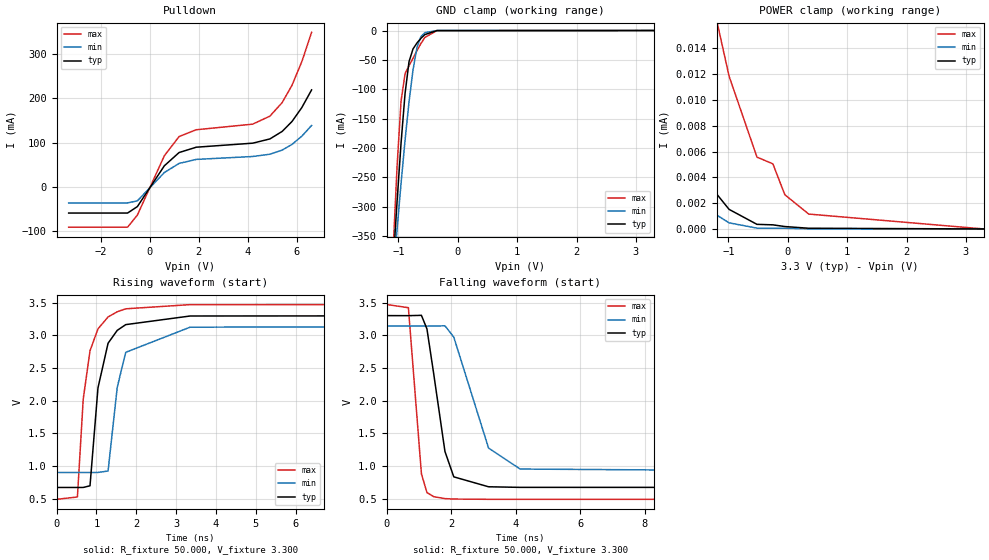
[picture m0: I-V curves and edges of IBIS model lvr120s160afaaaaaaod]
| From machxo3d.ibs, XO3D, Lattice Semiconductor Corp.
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|   Model lvr120s160afaaaaaaod
[Model] lvr120s160afaaaaaaod
Model_type I/O_open_drain
Polarity   Non-Inverting
Enable   Active-Low
Vinl =  0.420V
Vinh =  0.780V
Vmeas =  0.600V
Cref =  0.0F
Rref = 10.00k
Vref = 1.20V
C_comp   4.200pF   3.800pF   7.500pF
[Temperature Range]   25.000   0.105k   -40.000
[Voltage Range]   3.300V   3.140V   3.470V
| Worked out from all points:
|   slope of the pulldown table from 0 to 0.495 V, typ, clamps not added: 12.2 ohm
|   GND clamp passes 1 mA (typ) near -0.43 V on its own axis
|   rising waveform, R_fixture 50.000, V_fixture 3.300: 20-80 % time 312ps typ, 316ps min, 316ps max; typ from 0.669 V to 3.3 V
|   falling waveform, R_fixture 50.000, V_fixture 3.300: 20-80 % time 463ps typ, 830ps min, 252ps max; typ from 3.3 V to 0.669 V
[Pulldown]
|Voltage   I(typ)   I(min)   I(max)
-3.3V     -58.64mA   -35.81mA   -90.41mA
-900mV    -58.64mA   -35.81mA   -90.41mA
-500mV    -44.08mA   -31.23mA   -63.19mA
600mV     47.81mA    32.63mA    70.46mA
1.2V      77.59mA    53.08mA    113.6mA
1.9V      89.57mA    62.1mA     128.9mA
4.2V      98.64mA    68.65mA    141.5mA
4.9V      108.2mA    73.77mA    159.5mA
5.4V      125.1mA    83.07mA    190mA
5.8V      147.4mA    95.86mA    228.9mA
6.2V      178.7mA    114.3mA    281.9mA
6.6V      218.6mA    138.5mA    348.2mA
[GND_clamp]
|Voltage   I(typ)   I(min)   I(max)
-3.3V     -4.507A    -3.482A    -6.263A
-1.089V   -398.4mA   -420.6mA   -374.7mA
-1.022V   -290.7mA   -338.6mA   -230.6mA
-955mV    -191.4mA   -260.2mA   -120.1mA
-888mV    -107.5mA   -187mA     -73.69mA
-821mV    -53mA      -121.4mA   -59.83mA
-754mV    -31.41mA   -66.95mA   -47.44mA
-687mV    -21.17mA   -28.83mA   -34.23mA
-620mV    -13.21mA   -10.24mA   -21.98mA
-553mV    -6.877mA   -3.592mA   -11.71mA
-352mV    -122.8uA   -54.62uA   -209.3uA
3.3V      0A         0A         0A
[POWER_clamp]
|Voltage   I(typ)   I(min)   I(max)
-3.3V     530uA      347.3uA    956.2uA
-2.663V   63.57uA    15.44uA    254.2uA
-2.529V   27.42uA    10.98uA    148.7uA
-2.328V   15.78uA    8.532uA    64.82uA
-1.725V   7.398uA    3.714uA    31uA
-1.189V   2.659uA    1.053uA    15.99uA
-988mV    1.516uA    474.5nA    11.83uA
-519mV    357.5nA    63.32nA    5.567uA
-251mV    319nA      55.58nA    5.047uA
-50mV     187.6nA    55.58nA    2.655uA
352mV     56.19nA    7.349nA    1.154uA
3.3V      0A         0A         0A
[Ramp]
| variable   typ   min   max
dV/dt_r   1.578/0.313n   1.344/0.314n   1.789/0.315n
dV/dt_f   1.578/0.464n   1.345/0.827n   1.789/0.251n
R_load = 50.000
[Rising Waveform]
R_fixture= 50.000
V_fixture= 3.300
V_fixture_min= 3.140
V_fixture_max= 3.470
|time   V(typ)   V(min)   V(max)
0s        669.4mV    899.2mV    487.7mV
524ps     669.4mV    899.2mV    523.8mV
670ps     669.8mV    899.2mV    2.022V
840ps     694.8mV    899.2mV    2.762V
1.04ns    2.194V     899.3mV    3.097V
1.293ns   2.877V     921.1mV    3.279V
1.523ns   3.074V     2.202V     3.359V
1.736ns   3.162V     2.738V     3.404V
3.352ns   3.294V     3.123V     3.468V
20ns      3.3V       3.14V      3.47V
[Falling Waveform]
R_fixture= 50.000
V_fixture= 3.300
V_fixture_min= 3.140
V_fixture_max= 3.470
|time   V(typ)   V(min)   V(max)
0s        3.3V       3.14V      3.47V
677ps     3.299V     3.14V      3.421V
1.081ns   3.304V     3.14V      877mV
1.252ns   3.096V     3.139V     590.8mV
1.461ns   2.41V      3.14V      528.6mV
1.809ns   1.221V     3.144V     498.6mV
2.083ns   831.7mV    2.971V     491.8mV
3.16ns    679.7mV    1.272V     487.7mV
4.138ns   670.7mV    951.2mV    487.6mV
20ns      669.4mV    899.1mV    487.5mV
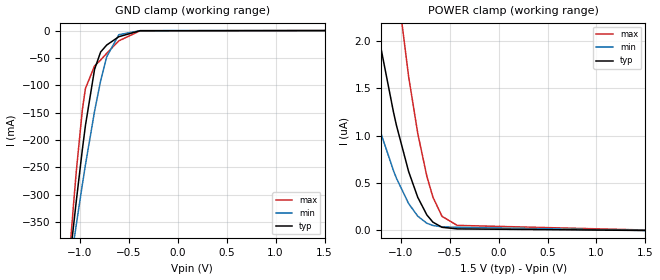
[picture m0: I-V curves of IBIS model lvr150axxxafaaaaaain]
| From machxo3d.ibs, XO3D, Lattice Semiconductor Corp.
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|   Model lvr150axxxafaaaaaain
[Model] lvr150axxxafaaaaaain
Model_type Input
Polarity   Non-Inverting
Enable   Active-High
Vinl =  0.375V
Vinh =  1.125V
C_comp   4.200pF   3.800pF   7.500pF
[Temperature Range]   25.000   0.105k   -40.000
[Voltage Range]   1.500V   1.430V   1.580V
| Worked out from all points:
|   GND clamp passes 1 mA (typ) near -0.44 V on its own axis
[GND_clamp]
|Voltage   I(typ)   I(min)   I(max)
-1.5V     -1.124A    -960.6mA   -1.411A
-1.097V   -411.6mA   -430.5mA   -393mA
-1.066V   -360.7mA   -392mA     -323mA
-1.035V   -311.1mA   -354.2mA   -256.8mA
-973mV    -216.9mA   -280.8mA   -144.3mA
-942mV    -173.5mA   -245.5mA   -105.7mA
-849mV    -71.09mA   -147.7mA   -64.65mA
-787mV    -39.21mA   -92.08mA   -53.73mA
-725mV    -26.45mA   -48.03mA   -41.63mA
-601mV    -11.2mA    -7.579mA   -18.78mA
-384mV    -277.2uA   -118.5uA   -427.8uA
1.5V      0A         0A         0A
[POWER_clamp]
|Voltage   I(typ)   I(min)   I(max)
-1.5V     4.025uA    2.303uA    8.505uA
-1.321V   2.683uA    1.48uA     5.831uA
-1.197V   1.901uA    1.012uA    4.26uA
-1.073V   1.248uA    630.2nA    2.932uA
-1.042V   1.105uA    548.9nA    2.638uA
-918mV    620.2nA    283.3nA    1.62uA
-825mV    349.5nA    150.8nA    1.023uA
-732mV    163.5nA    76.19nA    570.1nA
-670mV    87.46nA    52.45nA    351.3nA
-577mV    33.55nA    38.48nA    148.5nA
-422mV    16.59nA    33.11nA    53.69nA
1.5V      0A         0A         4.733nA
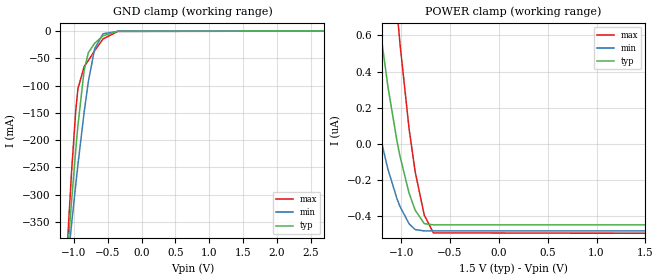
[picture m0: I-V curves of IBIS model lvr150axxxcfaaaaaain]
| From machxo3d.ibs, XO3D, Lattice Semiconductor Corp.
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|   Model lvr150axxxcfaaaaaain
[Model] lvr150axxxcfaaaaaain
Model_type Input
Polarity   Non-Inverting
Enable   Active-High
Vinl =  0.375V
Vinh =  1.125V
C_comp   4.200pF   3.800pF   7.500pF
[Temperature Range]   25.000   0.105k   -40.000
[Voltage Range]   1.500V   1.430V   1.580V
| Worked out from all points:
|   GND clamp passes 1 mA (typ) near -0.43 V on its own axis
[GND_clamp]
|Voltage   I(typ)   I(min)   I(max)
-1.5V     -1.124A    -960.6mA   -1.411A
-1.097V   -411.6mA   -430.5mA   -393mA
-1.066V   -360.8mA   -392.1mA   -323.1mA
-1.035V   -311.1mA   -354.2mA   -256.8mA
-973mV    -216.9mA   -280.8mA   -144.4mA
-942mV    -173.5mA   -245.5mA   -105.8mA
-849mV    -71.14mA   -147.7mA   -64.71mA
-787mV    -39.25mA   -92.1mA    -53.8mA
-694mV    -22.1mA    -31.86mA   -35.61mA
-570mV    -8.334mA   -4.716mA   -14.13mA
-353mV    -196.2uA   -97.38uA   -320uA
3V        108.2uA    41.36uA    254.4uA
[POWER_clamp]
|Voltage   I(typ)   I(min)   I(max)
-1.5V     2.189uA    965.6nA    5.317uA
-1.414V   1.654uA    640.9nA    4.2uA
-1.321V   1.138uA    331.9nA    3.121uA
-1.228V   692.2nA    73.47nA    2.187uA
-1.135V   318.1nA    -139.5nA   1.393uA
-1.042V   16.04nA    -303.5nA   739.6nA
-1.011V   -68.48nA   -346.9nA   552.4nA
-918mV    -272.6nA   -441.9nA   82.64nA
-856mV    -366.5nA   -474.2nA   -154.1nA
-763mV    -441nA     -481.2nA   -393.6nA
-670mV    -447.8nA   -481.2nA   -492.2nA
1.5V      -447.8nA   -481.2nA   -494.4nA
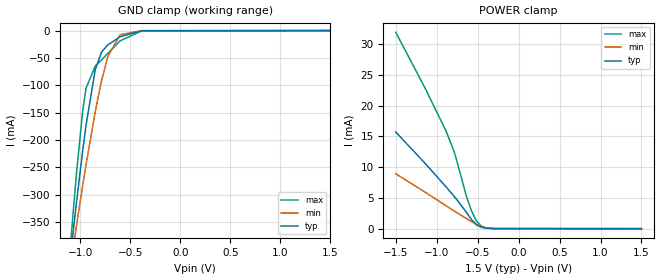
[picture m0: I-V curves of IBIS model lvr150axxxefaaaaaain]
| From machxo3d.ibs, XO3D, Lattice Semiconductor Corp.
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|   Model lvr150axxxefaaaaaain
[Model] lvr150axxxefaaaaaain
Model_type Input
Polarity   Non-Inverting
Enable   Active-High
Vinl =  0.375V
Vinh =  1.125V
C_comp   4.200pF   3.800pF   7.500pF
[Temperature Range]   25.000   0.105k   -40.000
[Voltage Range]   1.500V   1.430V   1.580V
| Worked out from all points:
|   GND clamp passes 1 mA (typ) near -0.44 V on its own axis
|   POWER clamp passes 1 mA (typ) near -0.54 V on its own axis
[GND_clamp]
|Voltage   I(typ)   I(min)   I(max)
-1.5V     -1.124A    -960.6mA   -1.411A
-1.097V   -411.6mA   -430.5mA   -393mA
-1.066V   -360.7mA   -392mA     -323mA
-1.035V   -311.1mA   -354.2mA   -256.8mA
-973mV    -216.9mA   -280.8mA   -144.3mA
-942mV    -173.5mA   -245.5mA   -105.7mA
-849mV    -71.09mA   -147.7mA   -64.65mA
-787mV    -39.21mA   -92.08mA   -53.73mA
-725mV    -26.45mA   -48.03mA   -41.63mA
-601mV    -11.2mA    -7.579mA   -18.78mA
-384mV    -277.2uA   -118.5uA   -427.8uA
1.5V      0A         0A         0A
[POWER_clamp]
|Voltage   I(typ)   I(min)   I(max)
-1.5V     15.72mA    8.93mA     31.93mA
-1.135V   10.52mA    5.88mA     22.68mA
-887mV    6.814mA    3.727mA    15.89mA
-794mV    5.361mA    2.934mA    12.77mA
-763mV    4.86mA     2.673mA    11.43mA
-639mV    2.682mA    1.649mA    5.339mA
-577mV    1.517mA    1.161mA    2.935mA
-515mV    644.1uA    707.7uA    1.253mA
-453mV    212.3uA    331.2uA    376.3uA
-391mV    62.92uA    103uA      90.27uA
-298mV    9.449uA    12.24uA    9.437uA
1.5V      0A         0A         4.733nA
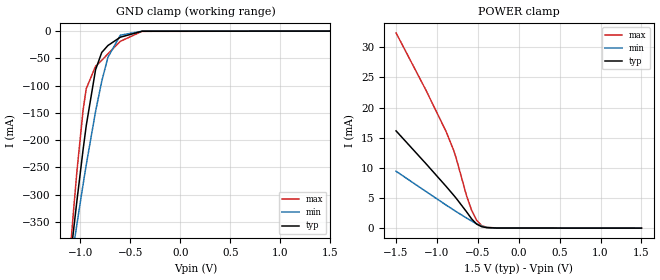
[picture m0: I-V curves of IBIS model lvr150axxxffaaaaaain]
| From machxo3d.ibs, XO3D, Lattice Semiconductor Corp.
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|   Model lvr150axxxffaaaaaain
[Model] lvr150axxxffaaaaaain
Model_type Input
Polarity   Non-Inverting
Enable   Active-High
Vinl =  0.375V
Vinh =  1.125V
C_comp   4.200pF   3.800pF   7.500pF
[Temperature Range]   25.000   0.105k   -40.000
[Voltage Range]   1.500V   1.430V   1.580V
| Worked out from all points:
|   GND clamp passes 1 mA (typ) near -0.44 V on its own axis
|   POWER clamp passes 1 mA (typ) near -0.54 V on its own axis
[GND_clamp]
|Voltage   I(typ)   I(min)   I(max)
-1.5V     -1.124A    -960.6mA   -1.411A
-1.097V   -411.6mA   -430.5mA   -393mA
-1.066V   -360.7mA   -392.1mA   -323mA
-1.035V   -311.1mA   -354.2mA   -256.8mA
-973mV    -216.9mA   -280.8mA   -144.3mA
-942mV    -173.5mA   -245.5mA   -105.7mA
-849mV    -71.1mA    -147.7mA   -64.67mA
-787mV    -39.22mA   -92.08mA   -53.75mA
-725mV    -26.46mA   -48.04mA   -41.66mA
-601mV    -11.21mA   -7.587mA   -18.81mA
-384mV    -296.7uA   -129.3uA   -468.7uA
1.5V      -39.25nA   0A         -8.28uA
[POWER_clamp]
|Voltage   I(typ)   I(min)   I(max)
-1.5V     16.13mA    9.435mA    32.38mA
-1.135V   10.7mA     6.085mA    22.89mA
-887mV    6.911mA    3.817mA    15.98mA
-794mV    5.433mA    2.998mA    12.85mA
-763mV    4.924mA    2.729mA    11.51mA
-639mV    2.724mA    1.684mA    5.401mA
-577mV    1.551mA    1.188mA    2.986mA
-515mV    672.4uA    729.1uA    1.295mA
-453mV    238.1uA    348.6uA    415uA
-391mV    86.84uA    117.8uA    129.3uA
-267mV    21.99uA    16.14uA    35.18uA
1.5V      0A         0A         0A
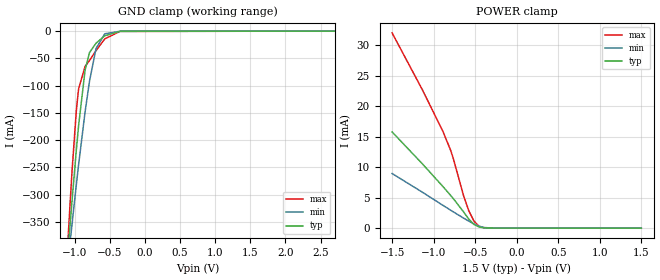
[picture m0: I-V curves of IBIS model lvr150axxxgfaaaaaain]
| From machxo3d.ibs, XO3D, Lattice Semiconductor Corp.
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|   Model lvr150axxxgfaaaaaain
[Model] lvr150axxxgfaaaaaain
Model_type Input
Polarity   Non-Inverting
Enable   Active-High
Vinl =  0.375V
Vinh =  1.125V
C_comp   4.200pF   3.800pF   7.500pF
[Temperature Range]   25.000   0.105k   -40.000
[Voltage Range]   1.500V   1.430V   1.580V
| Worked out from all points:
|   GND clamp passes 1 mA (typ) near -0.43 V on its own axis
|   POWER clamp passes 1 mA (typ) near -0.55 V on its own axis
[GND_clamp]
|Voltage   I(typ)   I(min)   I(max)
-1.5V     -1.124A    -960.6mA   -1.411A
-1.097V   -411.6mA   -430.5mA   -393mA
-1.066V   -360.8mA   -392.1mA   -323.1mA
-1.035V   -311.1mA   -354.2mA   -256.8mA
-973mV    -216.9mA   -280.8mA   -144.4mA
-942mV    -173.5mA   -245.5mA   -105.8mA
-849mV    -71.14mA   -147.7mA   -64.71mA
-787mV    -39.25mA   -92.1mA    -53.8mA
-694mV    -22.1mA    -31.86mA   -35.61mA
-570mV    -8.334mA   -4.716mA   -14.13mA
-353mV    -196.2uA   -97.38uA   -320uA
3V        108.2uA    41.36uA    254.4uA
[POWER_clamp]
|Voltage   I(typ)   I(min)   I(max)
-1.5V     15.78mA    8.958mA    32.02mA
-1.135V   10.54mA    5.894mA    22.68mA
-887mV    6.81mA     3.732mA    15.83mA
-794mV    5.35mA     2.936mA    12.73mA
-763mV    4.846mA    2.673mA    11.41mA
-639mV    2.663mA    1.646mA    5.294mA
-577mV    1.492mA    1.156mA    2.866mA
-515mV    615.8uA    702uA      1.171mA
-453mV    189.1uA    325.8uA    306.6uA
-391mV    49.53uA    99.25uA    52.72uA
-267mV    3.029uA    5.307uA    1.248uA
1.5V      0A         0A         -1.83nA
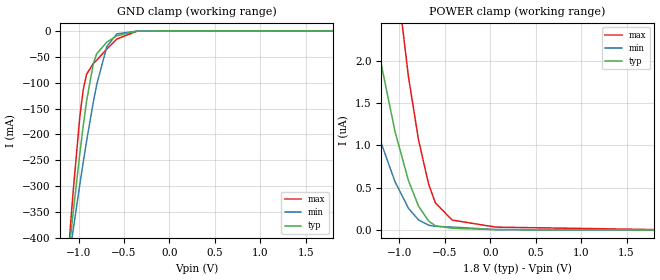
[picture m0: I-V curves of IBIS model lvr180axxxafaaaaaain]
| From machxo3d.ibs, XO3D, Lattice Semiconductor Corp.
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|   Model lvr180axxxafaaaaaain
[Model] lvr180axxxafaaaaaain
Model_type Input
Polarity   Non-Inverting
Enable   Active-High
Vinl =  0.630V
Vinh =  1.170V
C_comp   4.200pF   3.800pF   7.500pF
[Temperature Range]   25.000   0.105k   -40.000
[Voltage Range]   1.800V   1.710V   1.890V
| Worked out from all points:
|   GND clamp passes 1 mA (typ) near -0.44 V on its own axis
[GND_clamp]
|Voltage   I(typ)   I(min)   I(max)
-1.8V     -1.677A    -1.372A    -2.207A
-1.097V   -411.7mA   -430.5mA   -393mA
-1.06V    -351mA     -384.7mA   -309.9mA
-986mV    -235.9mA   -295.9mA   -164.7mA
-949mV    -183mA     -253.4mA   -113mA
-912mV    -135mA     -212.5mA   -83.36mA
-838mV    -63.19mA   -137.2mA   -62.7mA
-801mV    -43.96mA   -103.8mA   -56.29mA
-690mV    -21.52mA   -30.08mA   -34.76mA
-579mV    -9.088mA   -5.384mA   -15.36mA
-357mV    -138.9uA   -61.51uA   -230.6uA
1.8V      0A         0A         0A
[POWER_clamp]
|Voltage   I(typ)   I(min)   I(max)
-1.8V     6.931uA    4.083uA    15.57uA
-1.641V   5.346uA    3.088uA    12.2uA
-1.382V   3.169uA    1.748uA    7.531uA
-1.197V   1.939uA    1.016uA    4.862uA
-1.049V   1.163uA    569.7nA    3.145uA
-901mV    582.6nA    256.8nA    1.81uA
-790mV    282.1nA    118.1nA    1.064uA
-679mV    105nA      56.38nA    541.8nA
-605mV    50.57nA    42.35nA    321.5nA
-420mV    20nA       34.19nA    117nA
61mV      3.858nA    4.424nA    33.59nA
1.8V      0A         0A         4.849nA
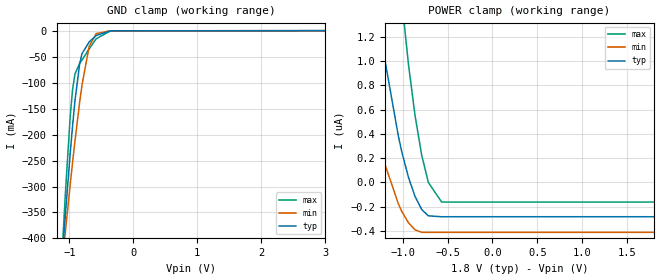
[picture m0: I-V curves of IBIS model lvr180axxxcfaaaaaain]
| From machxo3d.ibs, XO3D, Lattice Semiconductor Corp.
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|   Model lvr180axxxcfaaaaaain
[Model] lvr180axxxcfaaaaaain
Model_type Input
Polarity   Non-Inverting
Enable   Active-High
Vinl =  0.630V
Vinh =  1.170V
C_comp   4.200pF   3.800pF   7.500pF
[Temperature Range]   25.000   0.105k   -40.000
[Voltage Range]   1.800V   1.710V   1.890V
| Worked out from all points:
|   GND clamp passes 1 mA (typ) near -0.43 V on its own axis
[GND_clamp]
|Voltage   I(typ)   I(min)   I(max)
-1.8V     -1.677A    -1.372A    -2.207A
-1.097V   -411.7mA   -430.5mA   -393mA
-1.06V    -351.1mA   -384.7mA   -309.9mA
-986mV    -236mA     -295.9mA   -164.8mA
-949mV    -183.1mA   -253.4mA   -113.1mA
-912mV    -135mA     -212.5mA   -83.42mA
-838mV    -63.23mA   -137.2mA   -62.76mA
-801mV    -44mA      -103.8mA   -56.36mA
-690mV    -21.58mA   -30.12mA   -34.84mA
-579mV    -9.15mA    -5.432mA   -15.46mA
-357mV    -210.4uA   -103.6uA   -340.3uA
3.6V      109.8uA    43.45uA    257.2uA
[POWER_clamp]
|Voltage   I(typ)   I(min)   I(max)
-1.8V     5.628uA    2.78uA     14.07uA
-1.604V   3.73uA     1.682uA    9.635uA
-1.308V   1.587uA    465.9nA    4.652uA
-1.197V   993.1nA    141.4nA    3.268uA
-1.049V   375.2nA    -179.1nA   1.801uA
-1.012V   251.7nA    -238.8nA   1.5uA
-938mV    42.25nA    -332.5nA   973.7nA
-864mV    -116.4nA   -390.2nA   548.9nA
-790mV    -222.7nA   -411.1nA   224.4nA
-716mV    -275.4nA   -411.1nA   440pA
-568mV    -282.7nA   -411.1nA   -161.8nA
1.8V      -282.7nA   -411.1nA   -161.8nA
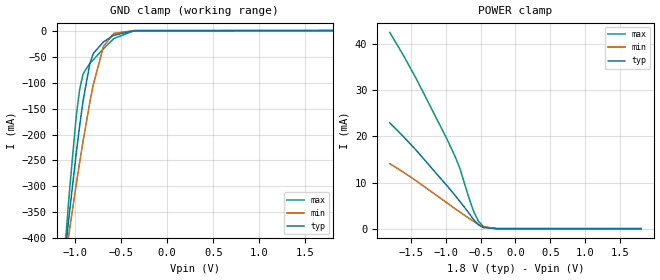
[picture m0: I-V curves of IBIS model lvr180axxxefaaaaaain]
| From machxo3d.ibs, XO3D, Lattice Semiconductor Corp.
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|   Model lvr180axxxefaaaaaain
[Model] lvr180axxxefaaaaaain
Model_type Input
Polarity   Non-Inverting
Enable   Active-High
Vinl =  0.630V
Vinh =  1.170V
C_comp   4.200pF   3.800pF   7.500pF
[Temperature Range]   25.000   0.105k   -40.000
[Voltage Range]   1.800V   1.710V   1.890V
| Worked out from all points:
|   GND clamp passes 1 mA (typ) near -0.44 V on its own axis
|   POWER clamp passes 1 mA (typ) near -0.54 V on its own axis
[GND_clamp]
|Voltage   I(typ)   I(min)   I(max)
-1.8V     -1.677A    -1.372A    -2.207A
-1.097V   -411.7mA   -430.5mA   -393mA
-1.06V    -351mA     -384.7mA   -309.9mA
-986mV    -235.9mA   -295.9mA   -164.7mA
-949mV    -183mA     -253.4mA   -113mA
-912mV    -135mA     -212.5mA   -83.36mA
-838mV    -63.19mA   -137.2mA   -62.7mA
-801mV    -43.96mA   -103.8mA   -56.29mA
-690mV    -21.52mA   -30.08mA   -34.76mA
-579mV    -9.088mA   -5.384mA   -15.36mA
-357mV    -138.9uA   -61.51uA   -230.6uA
1.8V      0A         0A         0A
[POWER_clamp]
|Voltage   I(typ)   I(min)   I(max)
-1.8V     22.96mA    14.12mA    42.58mA
-1.604V   19.99mA    12.25mA    37.59mA
-1.419V   16.97mA    10.35mA    32.49mA
-975mV    9.22mA     5.53mA     19.28mA
-864mV    7.199mA    4.329mA    15.63mA
-790mV    5.815mA    3.54mA     12.83mA
-679mV    3.632mA    2.381mA    7.284mA
-605mV    2.09mA     1.639mA    3.984mA
-531mV    838.2uA    949.9uA    1.628mA
-457mV    233.3uA    387uA      417.6uA
-272mV    5.864uA    7.033uA    5.504uA
1.8V      0A         0A         4.849nA
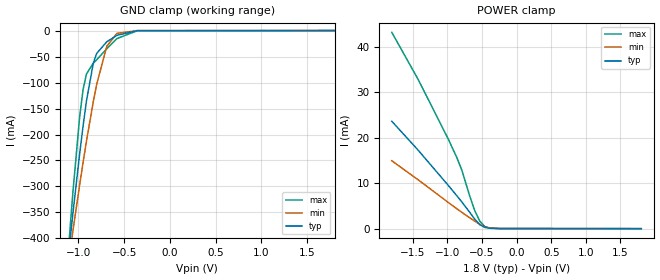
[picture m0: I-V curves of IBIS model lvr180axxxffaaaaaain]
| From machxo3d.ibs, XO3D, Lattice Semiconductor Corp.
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|   Model lvr180axxxffaaaaaain
[Model] lvr180axxxffaaaaaain
Model_type Input
Polarity   Non-Inverting
Enable   Active-High
Vinl =  0.630V
Vinh =  1.170V
C_comp   4.200pF   3.800pF   7.500pF
[Temperature Range]   25.000   0.105k   -40.000
[Voltage Range]   1.800V   1.710V   1.890V
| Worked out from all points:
|   GND clamp passes 1 mA (typ) near -0.43 V on its own axis
|   POWER clamp passes 1 mA (typ) near -0.54 V on its own axis
[GND_clamp]
|Voltage   I(typ)   I(min)   I(max)
-1.8V     -1.677A    -1.372A    -2.207A
-1.097V   -411.7mA   -430.5mA   -393mA
-1.06V    -351.1mA   -384.7mA   -309.9mA
-986mV    -236mA     -295.9mA   -164.7mA
-949mV    -183mA     -253.4mA   -113.1mA
-912mV    -135mA     -212.5mA   -83.39mA
-838mV    -63.2mA    -137.2mA   -62.73mA
-801mV    -43.97mA   -103.8mA   -56.32mA
-690mV    -21.54mA   -30.09mA   -34.79mA
-579mV    -9.111mA   -5.399mA   -15.41mA
-357mV    -171.9uA   -80.5uA    -290.6uA
1.8V      -9.206nA   0A         -10.91uA
[POWER_clamp]
|Voltage   I(typ)   I(min)   I(max)
-1.8V     23.65mA    14.95mA    43.22mA
-1.419V   17.27mA    10.75mA    32.84mA
-975mV    9.34mA     5.652mA    19.4mA
-864mV    7.287mA    4.412mA    15.72mA
-790mV    5.884mA    3.603mA    12.91mA
-679mV    3.68mA     2.424mA    7.353mA
-605mV    2.129mA    1.672mA    4.04mA
-531mV    870.5uA    975.4uA    1.674mA
-457mV    262.6uA    407.5uA    459.9uA
-383mV    82.85uA    106.6uA    121.5uA
-235mV    20.41uA    13.84uA    33.11uA
1.8V      0A         0A         0A
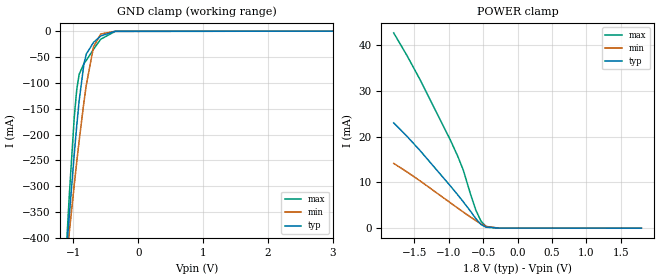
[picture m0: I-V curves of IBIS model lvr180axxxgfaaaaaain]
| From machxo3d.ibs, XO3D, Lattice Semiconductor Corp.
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|   Model lvr180axxxgfaaaaaain
[Model] lvr180axxxgfaaaaaain
Model_type Input
Polarity   Non-Inverting
Enable   Active-High
Vinl =  0.630V
Vinh =  1.170V
C_comp   4.200pF   3.800pF   7.500pF
[Temperature Range]   25.000   0.105k   -40.000
[Voltage Range]   1.800V   1.710V   1.890V
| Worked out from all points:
|   GND clamp passes 1 mA (typ) near -0.43 V on its own axis
|   POWER clamp passes 1 mA (typ) near -0.54 V on its own axis
[GND_clamp]
|Voltage   I(typ)   I(min)   I(max)
-1.8V     -1.677A    -1.372A    -2.207A
-1.097V   -411.7mA   -430.5mA   -393mA
-1.06V    -351.1mA   -384.7mA   -309.9mA
-986mV    -236mA     -295.9mA   -164.8mA
-949mV    -183.1mA   -253.4mA   -113.1mA
-912mV    -135mA     -212.5mA   -83.42mA
-838mV    -63.23mA   -137.2mA   -62.76mA
-801mV    -44mA      -103.8mA   -56.36mA
-690mV    -21.58mA   -30.12mA   -34.84mA
-579mV    -9.15mA    -5.432mA   -15.46mA
-357mV    -210.4uA   -103.6uA   -340.3uA
3.6V      109.8uA    43.45uA    257.2uA
[POWER_clamp]
|Voltage   I(typ)   I(min)   I(max)
-1.8V     23.01mA    14.15mA    42.67mA
-1.604V   20.03mA    12.27mA    37.65mA
-1.419V   17mA       10.36mA    32.52mA
-975mV    9.214mA    5.534mA    19.22mA
-864mV    7.184mA    4.33mA     15.56mA
-790mV    5.795mA    3.538mA    12.77mA
-679mV    3.608mA    2.377mA    7.234mA
-605mV    2.063mA    1.633mA    3.91mA
-531mV    807.6uA    943.4uA    1.541mA
-457mV    208.6uA    381.1uA    343.4uA
-272mV    3.657uA    6.158uA    1.653uA
1.8V      0A         0A         0A
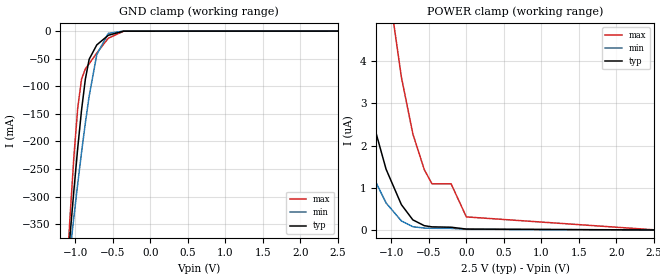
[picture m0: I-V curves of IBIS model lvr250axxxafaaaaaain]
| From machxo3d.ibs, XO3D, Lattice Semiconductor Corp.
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|   Model lvr250axxxafaaaaaain
[Model] lvr250axxxafaaaaaain
Model_type Input
Polarity   Non-Inverting
Enable   Active-High
Vinl =  0.700V
Vinh =  1.700V
C_comp   4.200pF   3.800pF   7.500pF
[Temperature Range]   25.000   0.105k   -40.000
[Voltage Range]   2.500V   2.380V   2.630V
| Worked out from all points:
|   GND clamp passes 1 mA (typ) near -0.43 V on its own axis
[GND_clamp]
|Voltage   I(typ)   I(min)   I(max)
-2.5V     -2.99A     -2.35A     -4.091A
-1.123V   -455.1mA   -463.2mA   -453.7mA
-1.072V   -370.5mA   -399.5mA   -336.3mA
-1.021V   -289.2mA   -337.4mA   -228.6mA
-970mV    -212.6mA   -277.3mA   -139.9mA
-919mV    -143.6mA   -220.1mA   -87.38mA
-868mV    -87.38mA   -166.5mA   -68.43mA
-817mV    -50.94mA   -117.8mA   -59.11mA
-715mV    -24.98mA   -42.37mA   -39.68mA
-562mV    -7.604mA   -4.134mA   -12.92mA
-358mV    -143.3uA   -63.27uA   -238.1uA
2.5V      0A         0A         0A
[POWER_clamp]
|Voltage   I(typ)   I(min)   I(max)
-2.5V     16.62uA    10.08uA    44.45uA
-2.09V    10.83uA    6.3uA      30.28uA
-1.682V   6.13uA     3.369uA    18.54uA
-1.376V   3.399uA    1.745uA    11.5uA
-1.07V    1.44uA     640.5nA    6.167uA
-866mV    600.8nA    214.7nA    3.625uA
-713mV    239.4nA    76.84nA    2.278uA
-560mV    101.4nA    44.89nA    1.428uA
-458mV    73.62nA    40.23nA    1.094uA
-203mV    64.97nA    37.73nA    1.094uA
1mV       21.5nA     15.07nA    309.5nA
2.5V      0A         0A         4.349nA
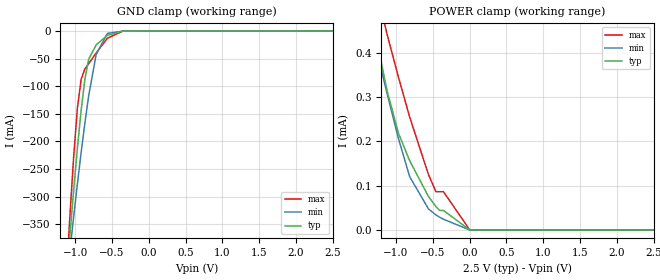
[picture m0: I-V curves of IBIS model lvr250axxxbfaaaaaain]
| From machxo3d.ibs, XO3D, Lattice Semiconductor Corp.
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|   Model lvr250axxxbfaaaaaain
[Model] lvr250axxxbfaaaaaain
Model_type Input
Polarity   Non-Inverting
Enable   Active-High
Vinl =  0.700V
Vinh =  1.700V
C_comp   4.200pF   3.800pF   7.500pF
[Temperature Range]   25.000   0.105k   -40.000
[Voltage Range]   2.500V   2.380V   2.630V
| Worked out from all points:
|   GND clamp passes 1 mA (typ) near -0.43 V on its own axis
|   POWER clamp passes 1 mA (typ) near -1.90 V on its own axis
[GND_clamp]
|Voltage   I(typ)   I(min)   I(max)
-2.5V     -2.99A     -2.35A     -4.091A
-1.123V   -455.2mA   -463.2mA   -453.7mA
-1.072V   -370.6mA   -399.5mA   -336.4mA
-1.021V   -289.2mA   -337.4mA   -228.6mA
-970mV    -212.6mA   -277.4mA   -140mA
-919mV    -143.7mA   -220.1mA   -87.43mA
-868mV    -87.42mA   -166.5mA   -68.48mA
-817mV    -50.97mA   -117.8mA   -59.16mA
-715mV    -25.02mA   -42.39mA   -39.74mA
-562mV    -7.656mA   -4.169mA   -13.01mA
-358mV    -214uA     -108.4uA   -353.1uA
2.5V      18.48nA    0A         -19.28uA
[POWER_clamp]
|Voltage   I(typ)   I(min)   I(max)
-2.5V     1.538mA    1.365mA    2.126mA
-1.325V   482.6uA    450.2uA    591.6uA
-1.274V   438.4uA    413.8uA    546.7uA
-1.121V   313.5uA    307.1uA    441uA
-968mV    218.6uA    206.5uA    345.2uA
-815mV    156.3uA    120.3uA    254.8uA
-560mV    75.6uA     47.55uA    125.2uA
-458mV    52.76uA    33.88uA    86.36uA
-407mV    44.02uA    28.68uA    86.36uA
-356mV    44.02uA    24.22uA    86.36uA
1mV       0A         0A         152.5nA
2.5V      0A         0A         0A
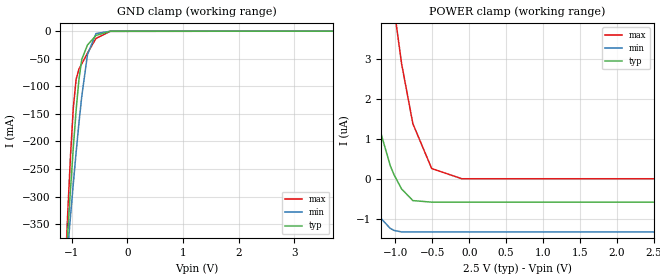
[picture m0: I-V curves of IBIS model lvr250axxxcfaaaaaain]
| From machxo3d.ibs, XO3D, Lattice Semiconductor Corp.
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|   Model lvr250axxxcfaaaaaain
[Model] lvr250axxxcfaaaaaain
Model_type Input
Polarity   Non-Inverting
Enable   Active-High
Vinl =  0.700V
Vinh =  1.700V
C_comp   4.200pF   3.800pF   7.500pF
[Temperature Range]   25.000   0.105k   -40.000
[Voltage Range]   2.500V   2.380V   2.630V
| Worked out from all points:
|   GND clamp passes 1 mA (typ) near -0.43 V on its own axis
[GND_clamp]
|Voltage   I(typ)   I(min)   I(max)
-2.5V     -2.99A     -2.35A     -4.091A
-1.123V   -455.2mA   -463.2mA   -453.7mA
-1.072V   -370.6mA   -399.5mA   -336.4mA
-1.021V   -289.2mA   -337.4mA   -228.6mA
-970mV    -212.6mA   -277.4mA   -140mA
-919mV    -143.7mA   -220.1mA   -87.44mA
-868mV    -87.42mA   -166.5mA   -68.49mA
-817mV    -50.98mA   -117.8mA   -59.18mA
-715mV    -25.03mA   -42.4mA    -39.75mA
-562mV    -7.668mA   -4.182mA   -13.02mA
-307mV    -104.3uA   -54uA      -191.8uA
5V        114uA      50.56uA    266.8uA
[POWER_clamp]
|Voltage   I(typ)   I(min)   I(max)
-2.5V     21.65uA    7.994uA    64.99uA
-2.192V   14.55uA    4.663uA    46.49uA
-1.886V   8.807uA    2.082uA    30.71uA
-1.58V    4.502uA    252.2nA    18.23uA
-1.325V   1.963uA    -734.2nA   10.5uA
-1.07V    325.4nA    -1.248uA   5.102uA
-1.019V   99.27nA    -1.296uA   4.283uA
-917mV    -255.8nA   -1.335uA   2.889uA
-764mV    -548.2nA   -1.335uA   1.381uA
-509mV    -587.6nA   -1.335uA   256.3nA
-101mV    -587.6nA   -1.335uA   0A
2.5V      -587.6nA   -1.335uA   0A
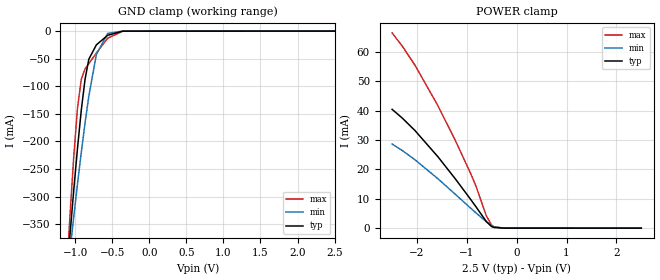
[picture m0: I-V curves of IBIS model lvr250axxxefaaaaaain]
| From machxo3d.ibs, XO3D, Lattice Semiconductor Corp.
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|   Model lvr250axxxefaaaaaain
[Model] lvr250axxxefaaaaaain
Model_type Input
Polarity   Non-Inverting
Enable   Active-High
Vinl =  0.700V
Vinh =  1.700V
C_comp   4.200pF   3.800pF   7.500pF
[Temperature Range]   25.000   0.105k   -40.000
[Voltage Range]   2.500V   2.380V   2.630V
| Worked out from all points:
|   GND clamp passes 1 mA (typ) near -0.43 V on its own axis
|   POWER clamp passes 1 mA (typ) near -0.54 V on its own axis
[GND_clamp]
|Voltage   I(typ)   I(min)   I(max)
-2.5V     -2.99A     -2.35A     -4.091A
-1.123V   -455.1mA   -463.2mA   -453.7mA
-1.072V   -370.5mA   -399.5mA   -336.3mA
-1.021V   -289.2mA   -337.4mA   -228.6mA
-970mV    -212.6mA   -277.3mA   -139.9mA
-919mV    -143.6mA   -220.1mA   -87.38mA
-868mV    -87.38mA   -166.5mA   -68.43mA
-817mV    -50.94mA   -117.8mA   -59.11mA
-715mV    -24.98mA   -42.37mA   -39.68mA
-562mV    -7.604mA   -4.134mA   -12.92mA
-358mV    -143.3uA   -63.27uA   -238.1uA
2.5V      0A         0A         0A
[POWER_clamp]
|Voltage   I(typ)   I(min)   I(max)
-2.5V     40.49mA    28.66mA    66.53mA
-2.294V   37.48mA    26.44mA    61.99mA
-2.039V   33.22mA    23.28mA    55.47mA
-1.58V    24.32mA    16.83mA    41.7mA
-1.223V   16.61mA    11.41mA    29.6mA
-917mV    9.64mA     6.717mA    18.35mA
-815mV    7.232mA    5.177mA    14.23mA
-611mV    2.3mA      2.221mA    4.282mA
-509mV    606.6uA    937.1uA    1.171mA
-458mV    246.2uA    452.1uA    442.4uA
-254mV    4.78uA     5.131uA    5.129uA
2.5V      0A         0A         4.349nA
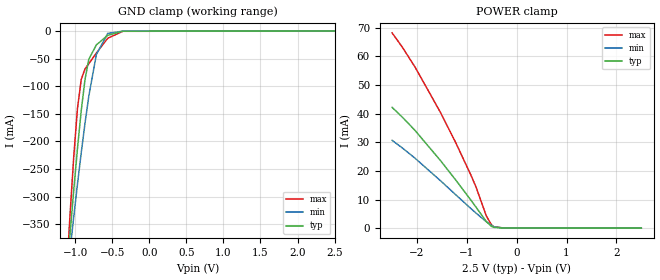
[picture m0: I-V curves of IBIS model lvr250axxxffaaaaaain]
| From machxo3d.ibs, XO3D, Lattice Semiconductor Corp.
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|   Model lvr250axxxffaaaaaain
[Model] lvr250axxxffaaaaaain
Model_type Input
Polarity   Non-Inverting
Enable   Active-High
Vinl =  0.700V
Vinh =  1.700V
C_comp   4.200pF   3.800pF   7.500pF
[Temperature Range]   25.000   0.105k   -40.000
[Voltage Range]   2.500V   2.380V   2.630V
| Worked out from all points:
|   GND clamp passes 1 mA (typ) near -0.43 V on its own axis
|   POWER clamp passes 1 mA (typ) near -0.54 V on its own axis
[GND_clamp]
|Voltage   I(typ)   I(min)   I(max)
-2.5V     -2.99A     -2.35A     -4.091A
-1.123V   -455.2mA   -463.2mA   -453.7mA
-1.072V   -370.6mA   -399.5mA   -336.4mA
-1.021V   -289.2mA   -337.4mA   -228.6mA
-970mV    -212.6mA   -277.4mA   -140mA
-919mV    -143.7mA   -220.1mA   -87.43mA
-868mV    -87.42mA   -166.5mA   -68.48mA
-817mV    -50.97mA   -117.8mA   -59.16mA
-715mV    -25.02mA   -42.39mA   -39.74mA
-562mV    -7.656mA   -4.169mA   -13.01mA
-358mV    -214uA     -108.4uA   -353.1uA
2.5V      18.48nA    0A         -19.28uA
[POWER_clamp]
|Voltage   I(typ)   I(min)   I(max)
-2.5V     42.14mA    30.66mA    68.15mA
-2.294V   38.75mA    27.99mA    63.15mA
-2.039V   34.09mA    24.4mA     56.2mA
-1.529V   23.59mA    16.56mA    40.38mA
-1.223V   16.8mA     11.66mA    29.82mA
-917mV    9.741mA    6.82mA     18.46mA
-815mV    7.309mA    5.252mA    14.31mA
-611mV    2.343mA    2.261mA    4.34mA
-509mV    643uA      967uA      1.218mA
-458mV    281.4uA    478.7uA    489.6uA
-254mV    29.31uA    21.32uA    44.54uA
2.5V      0A         0A         0A
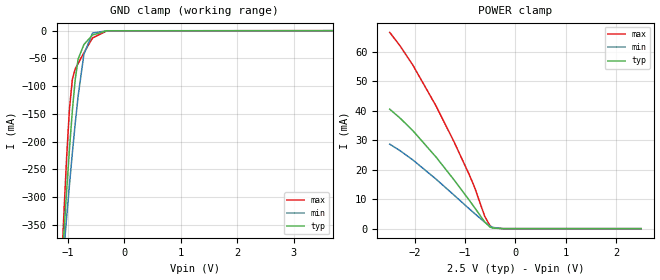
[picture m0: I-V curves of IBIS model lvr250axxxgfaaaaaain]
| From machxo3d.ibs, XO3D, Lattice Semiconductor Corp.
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|   Model lvr250axxxgfaaaaaain
[Model] lvr250axxxgfaaaaaain
Model_type Input
Polarity   Non-Inverting
Enable   Active-High
Vinl =  0.700V
Vinh =  1.700V
C_comp   4.200pF   3.800pF   7.500pF
[Temperature Range]   25.000   0.105k   -40.000
[Voltage Range]   2.500V   2.380V   2.630V
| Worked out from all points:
|   GND clamp passes 1 mA (typ) near -0.43 V on its own axis
|   POWER clamp passes 1 mA (typ) near -0.54 V on its own axis
[GND_clamp]
|Voltage   I(typ)   I(min)   I(max)
-2.5V     -2.99A     -2.35A     -4.091A
-1.123V   -455.2mA   -463.2mA   -453.7mA
-1.072V   -370.6mA   -399.5mA   -336.4mA
-1.021V   -289.2mA   -337.4mA   -228.6mA
-970mV    -212.6mA   -277.4mA   -140mA
-919mV    -143.7mA   -220.1mA   -87.44mA
-868mV    -87.42mA   -166.5mA   -68.49mA
-817mV    -50.98mA   -117.8mA   -59.18mA
-715mV    -25.03mA   -42.4mA    -39.75mA
-562mV    -7.668mA   -4.182mA   -13.02mA
-307mV    -104.3uA   -54uA      -191.8uA
5V        114uA      50.57uA    266.8uA
[POWER_clamp]
|Voltage   I(typ)   I(min)   I(max)
-2.5V     40.55mA    28.7mA     66.64mA
-2.294V   37.53mA    26.47mA    62.05mA
-2.039V   33.25mA    23.31mA    55.5mA
-1.58V    24.33mA    16.84mA    41.69mA
-1.223V   16.6mA     11.41mA    29.55mA
-917mV    9.617mA    6.713mA    18.27mA
-815mV    7.205mA    5.172mA    14.15mA
-611mV    2.266mA    2.213mA    4.191mA
-509mV    573.3uA    928.9uA    1.074mA
-458mV    219.2uA    444.8uA    361.5uA
-254mV    2.706uA    4.109uA    1.296uA
2.5V      0A         0A         0A
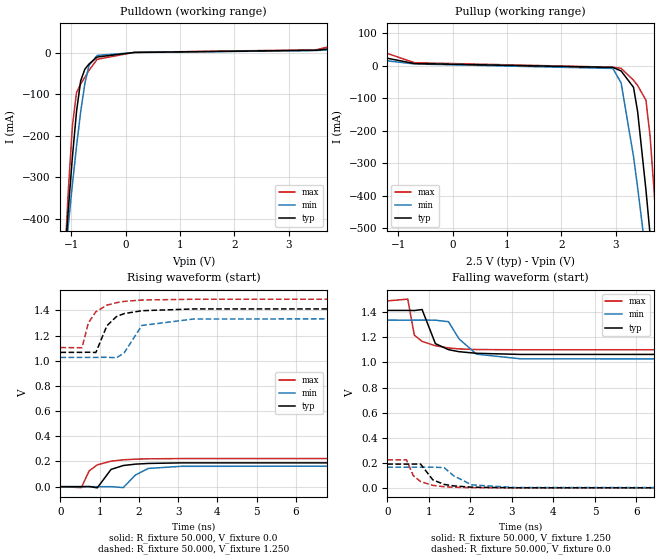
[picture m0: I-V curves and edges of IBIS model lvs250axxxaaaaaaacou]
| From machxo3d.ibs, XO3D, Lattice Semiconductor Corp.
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|   Model lvs250axxxaaaaaaacou
[Model] lvs250axxxaaaaaaacou
Model_type Output
Polarity   Non-Inverting
Enable   Active-High
Vmeas =  1.250V
Cref =  3.000pF
Rref =  50.000
Vref =  1.250V
C_comp   4.200pF   3.800pF   7.500pF
[Temperature Range]   25.000   0.105k   -40.000
[Voltage Range]   2.500V   2.380V   2.630V
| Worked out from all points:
|   slope of the pulldown table from 0 to 0.375 V, typ, clamps not added: 177 ohm
|   slope of the pullup table from 0 to 0.375 V, typ, clamps not added: 208 ohm
|   rising waveform, R_fixture 50.000, V_fixture 0.0: 20-80 % time 329ps typ, 366ps min, 368ps max; typ from 0 V to 0.19 V
|   rising waveform, R_fixture 50.000, V_fixture 1.250: 20-80 % time 356ps typ, 374ps min, 380ps max; typ from 1.07 V to 1.41 V
|   falling waveform, R_fixture 50.000, V_fixture 1.250: 20-80 % time 264ps typ, 413ps min, 208ps max; typ from 1.42 V to 1.06 V
|   falling waveform, R_fixture 50.000, V_fixture 0.0: 20-80 % time 360ps typ, 426ps min, 308ps max; typ from 0.19 V to 0 V
[Pulldown]
|Voltage   I(typ)   I(min)   I(max)
-2.5V     -3.262A    -2.545A    -4.486A
-1.132V   -515.9mA   -517.9mA   -523.2mA
-1.056V   -378.9mA   -415.3mA   -333.3mA
-980mV    -250.9mA   -316.8mA   -175.3mA
-904mV    -140.7mA   -224.5mA   -95.35mA
-828mV    -67.23mA   -141.9mA   -74.77mA
-752mV    -39.47mA   -74.37mA   -58.93mA
-676mV    -26.96mA   -30.36mA   -42.27mA
-524mV    -9.924mA   -6.066mA   -15.37mA
160mV     1.112mA    892.4uA    1.341mA
3.504V    6.376mA    5.751mA    7.472mA
5V        27.84mA    15.18mA    55.22mA
[Pullup]
|Voltage   I(typ)   I(min)   I(max)
-2.5V     65.23mA    40.43mA    111.6mA
-700mV    6.703mA    5.351mA    9.271mA
2.948V    -5.209mA   -8.351mA   -4.594mA
3.1V      -16.14mA   -53.15mA   -8.125mA
3.328V    -66.56mA   -279.6mA   -44.68mA
3.404V    -141.9mA   -375.9mA   -61.2mA
3.556V    -381.7mA   -581.6mA   -105.9mA
3.632V    -519mA     -688.4mA   -216.3mA
3.708V    -661.4mA   -796.9mA   -388.9mA
3.784V    -807.2mA   -906.6mA   -584.3mA
3.86V     -955.1mA   -1.017A    -789.9mA
5V        -3.266A    -2.731A    -4.105A
[Ramp]
| variable   typ   min   max
dV/dt_r   0.114/0.319n   99.074m/0.353n   0.134/0.364n
dV/dt_f   0.132/0.300n   0.110/0.478n   0.160/0.130n
R_load = 50.000
[Rising Waveform]
R_fixture= 50.000
V_fixture= 0.0
V_fixture_min= 0.0
V_fixture_max= 0.0
|time   V(typ)   V(min)   V(max)
0s        23.91nV    112.6nV    92.31nV
533ps     28.58uV    49.3uV     -7.442mV
732ps     1.118mV    24.33uV    125.9mV
938ps     -9.523mV   24.33uV    173.1mV
1.289ns   137mV      33.06uV    202.7mV
1.6ns     168mV      -7.208mV   213mV
1.907ns   178.9mV    91.93mV    218.5mV
2.237ns   184.4mV    144.7mV    221.1mV
3.073ns   189mV      161.7mV    223.2mV
20ns      189.8mV    165.1mV    223.2mV
[Rising Waveform]
R_fixture= 50.000
V_fixture= 1.250
V_fixture_min= 1.188
V_fixture_max= 1.313
|time   V(typ)   V(min)   V(max)
0s        1.067V     1.027V     1.105V
549ps     1.067V     1.027V     1.104V
711ps     1.068V     1.027V     1.301V
902ps     1.066V     1.027V     1.39V
1.184ns   1.279V     1.028V     1.442V
1.429ns   1.352V     1.024V     1.462V
1.625ns   1.375V     1.064V     1.472V
2.074ns   1.398V     1.281V     1.483V
3.393ns   1.412V     1.332V     1.489V
20ns      1.413V     1.337V     1.49V
[Falling Waveform]
R_fixture= 50.000
V_fixture= 1.250
V_fixture_min= 1.188
V_fixture_max= 1.313
|time   V(typ)   V(min)   V(max)
0s        1.415V     1.338V     1.491V
492ps     1.415V     1.337V     1.505V
650ps     1.414V     1.338V     1.218V
837ps     1.422V     1.338V     1.168V
1.158ns   1.15V      1.337V     1.133V
1.473ns   1.102V     1.325V     1.116V
1.724ns   1.086V     1.189V     1.108V
2.148ns   1.073V     1.066V     1.103V
3.208ns   1.064V     1.029V     1.101V
20ns      1.065V     1.025V     1.103V
[Falling Waveform]
R_fixture= 50.000
V_fixture= 0.0
V_fixture_min= 0.0
V_fixture_max= 0.0
|time   V(typ)   V(min)   V(max)
0s        189.6mV    164.9mV    223mV
462ps     189.5mV    164.7mV    223.2mV
624ps     189.6mV    164.8mV    98.25mV
801ps     189.8mV    164.9mV    49.94mV
1.095ns   64.05mV    164.9mV    20.14mV
1.367ns   27.68mV    161.8mV    9.159mV
1.593ns   15.83mV    97.51mV    4.723mV
2.031ns   5.288mV    23.79mV    1.721mV
3.067ns   698.5uV    2.963mV    209.9uV
20ns      -317.1nV   -15.64nV   -740.6nV
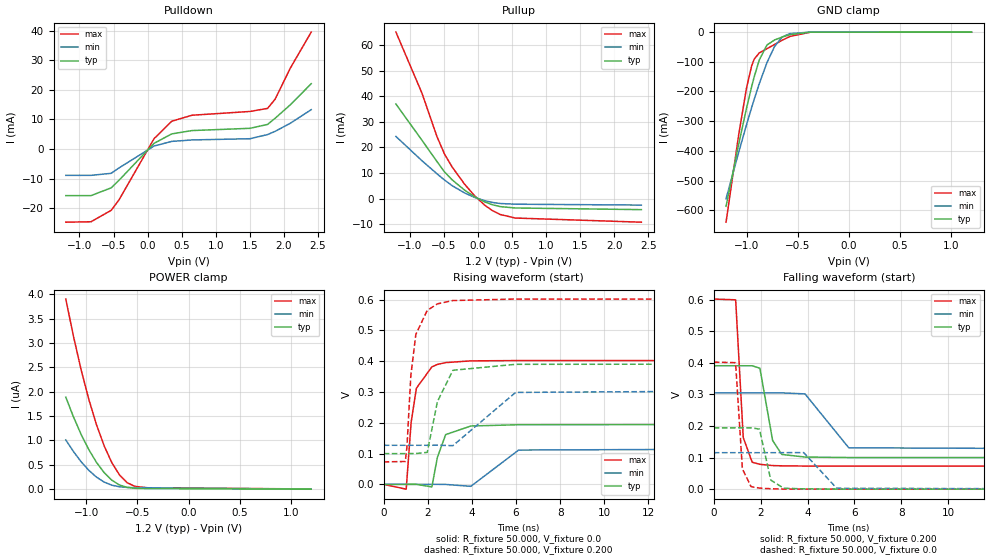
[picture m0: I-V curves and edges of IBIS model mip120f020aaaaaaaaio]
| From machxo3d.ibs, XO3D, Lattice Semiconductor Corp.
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|   Model mip120f020aaaaaaaaio
[Model] mip120f020aaaaaaaaio
Model_type I/O
Polarity   Non-Inverting
Enable   Active-Low
Vinl =  0.0V
Vinh =  0.400V
Vmeas =  0.200V
Cref =  3.000pF
Rref =  50.000
Vref =  0.200V
C_comp   4.200pF   3.800pF   7.500pF
[Temperature Range]   25.000   0.105k   -40.000
[Voltage Range]   1.200V   1.140V   1.260V
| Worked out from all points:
|   slope of the pulldown table from 0 to 0.18 V, typ, clamps not added: 55.1 ohm
|   slope of the pullup table from 0 to 0.18 V, typ, clamps not added: 85.3 ohm
|   GND clamp passes 1 mA (typ) near -0.44 V on its own axis
|   rising waveform, R_fixture 50.000, V_fixture 0.0: 20-80 % time 405ps typ, 582ps min, 395ps max; typ from 0 V to 0.194 V
|   rising waveform, R_fixture 50.000, V_fixture 0.200: 20-80 % time 466ps typ, 977ps min, 393ps max; typ from 0.1 V to 0.391 V
|   falling waveform, R_fixture 50.000, V_fixture 0.200: 20-80 % time 411ps typ, 903ps min, 199ps max; typ from 0.391 V to 0.1 V
|   falling waveform, R_fixture 50.000, V_fixture 0.0: 20-80 % time 333ps typ, 496ps min, 181ps max; typ from 0.194 V to 0 V
[Pulldown]
|Voltage   I(typ)   I(min)   I(max)
-1.2V     -15.77mA   -8.921mA   -24.76mA
-830mV    -15.77mA   -8.921mA   -24.61mA
-534mV    -13.14mA   -8.234mA   -20.74mA
-423mV    -10.67mA   -6.463mA   -17.35mA
95mV      1.91mA     997.3uA    3.496mA
354mV     5.095mA    2.558mA    9.38mA
650mV     6.221mA    3.05mA     11.4mA
1.501V    6.983mA    3.464mA    12.68mA
1.76V     8.299mA    4.874mA    13.72mA
1.871V    10.4mA     5.962mA    16.85mA
2.093V    14.92mA    8.691mA    27.32mA
2.4V      22.06mA    13.29mA    39.52mA
[Pullup]
|Voltage   I(typ)   I(min)   I(max)
-1.2V     36.95mA    24.29mA    65.09mA
-819mV    22.83mA    14.81mA    41.27mA
-597mV    14.43mA    9.66mA     24.15mA
-486mV    10.38mA    7.228mA    17.33mA
-375mV    7.309mA    5.026mA    12.31mA
-190mV    3.229mA    2.154mA    5.518mA
-42mV     628.1uA    407.3uA    979.6uA
106mV     -1.356mA   -861.5uA   -2.669mA
217mV     -2.425mA   -1.522mA   -4.729mA
328mV     -3.145mA   -1.941mA   -6.218mA
550mV     -3.688mA   -2.208mA   -7.621mA
2.4V      -4.336mA   -2.552mA   -9.245mA
[GND_clamp]
|Voltage   I(typ)   I(min)   I(max)
-1.2V     -586.8mA   -561.6mA   -640.4mA
-1.075V   -375.3mA   -403.2mA   -342.9mA
-1V       -256.8mA   -312.3mA   -188.8mA
-950mV    -184.3mA   -254.5mA   -114.1mA
-925mV    -151.1mA   -226.6mA   -91.28mA
-875mV    -93.98mA   -173.6mA   -70.02mA
-800mV    -43.52mA   -102.9mA   -56.06mA
-725mV    -26.41mA   -48.03mA   -41.59mA
-650mV    -16.51mA   -16.35mA   -27.18mA
-575mV    -8.675mA   -5.014mA   -14.71mA
-375mV    -184.4uA   -82.53uA   -274.8uA
1.2V      0A         0A         0A
[POWER_clamp]
|Voltage   I(typ)   I(min)   I(max)
-1.2V     1.889uA    1.011uA    3.905uA
-1.125V   1.485uA    772.5nA    3.141uA
-1.05V    1.124uA    563.1nA    2.451uA
-975mV    812.1nA    387.4nA    1.845uA
-900mV    550nA      247.6nA    1.324uA
-825mV    340.1nA    145.7nA    890.5nA
-750mV    184.9nA    81.63nA    545.5nA
-675mV    85.56nA    49.1nA     292.2nA
-600mV    35.84nA    35.98nA    132.8nA
-525mV    17.84nA    31.28nA    57.77nA
-400mV    11.63nA    28.62nA    28.93nA
1.2V      0A         0A         3.813nA
[Ramp]
| variable   typ   min   max
dV/dt_r   0.117/0.429n   69.294m/0.573n   0.241/0.398n
dV/dt_f   0.196/0.410n   97.283m/0.584n   0.346/0.350n
R_load = 50.000
[Rising Waveform]
R_fixture= 50.000
V_fixture= 0.0
V_fixture_min= 0.0
V_fixture_max= 0.0
|time   V(typ)   V(min)   V(max)
0s        4.708nV    57.48nV    2.342nV
1.022ns   13.41uV    13.77uV    -15.58mV
1.246ns   188.3uV    13.77uV    202mV
1.483ns   75.14uV    13.77uV    312.2mV
2.185ns   -8.253mV   64uV       381.7mV
2.434ns   87.54mV    167uV      389.6mV
2.811ns   161.7mV    -217.7uV   395.6mV
3.95ns    189.6mV    -6.395mV   401.2mV
6.117ns   193.8mV    111.5mV    402.2mV
20ns      194.3mV    115.5mV    402.3mV
[Rising Waveform]
R_fixture= 50.000
V_fixture= 0.200
V_fixture_min= 0.191
V_fixture_max= 0.211
|time   V(typ)   V(min)   V(max)
0s        99.98mV    127mV      73.06mV
981ps     99.97mV    127mV      74.26mV
1.056ns   100mV      127mV      121.9mV
1.232ns   100.1mV    127mV      353.6mV
1.458ns   100.1mV    127mV      487mV
1.976ns   104mV      127mV      565.4mV
2.437ns   269.1mV    127.2mV    586.4mV
3.138ns   370.7mV    125.8mV    597.2mV
5.979ns   390mV      298.7mV    602mV
20ns      390.8mV    304.8mV    602mV
[Falling Waveform]
R_fixture= 50.000
V_fixture= 0.200
V_fixture_min= 0.191
V_fixture_max= 0.211
|time   V(typ)   V(min)   V(max)
0s        390.8mV    304.8mV    602mV
933ps     390.8mV    304.8mV    599.6mV
1.257ns   390.8mV    304.8mV    163.4mV
1.639ns   390.7mV    304.8mV    85.23mV
1.967ns   383mV      304.8mV    78.69mV
2.509ns   154.3mV    304.7mV    74.72mV
2.898ns   110mV      304.9mV    73.93mV
3.89ns    101.7mV    301.7mV    73.21mV
5.756ns   100.2mV    131mV      73.05mV
20ns      99.97mV    127mV      73.04mV
[Falling Waveform]
R_fixture= 50.000
V_fixture= 0.0
V_fixture_min= 0.0
V_fixture_max= 0.0
|time   V(typ)   V(min)   V(max)
0s        194.3mV    115.5mV    402.3mV
930ps     194.3mV    115.5mV    400.5mV
1.22ns    194.3mV    115.5mV    64.34mV
1.587ns   194.3mV    115.5mV    8.153mV
1.948ns   190.2mV    115.5mV    3.321mV
2.432ns   28.63mV    115.5mV    1.341mV
2.978ns   3.099mV    115.6mV    380.1uV
3.836ns   939uV      115.8mV    93.53uV
5.242ns   193.8uV    2.879mV    14.43uV
20ns      3.523nV    -297.3nV   -626.4nV
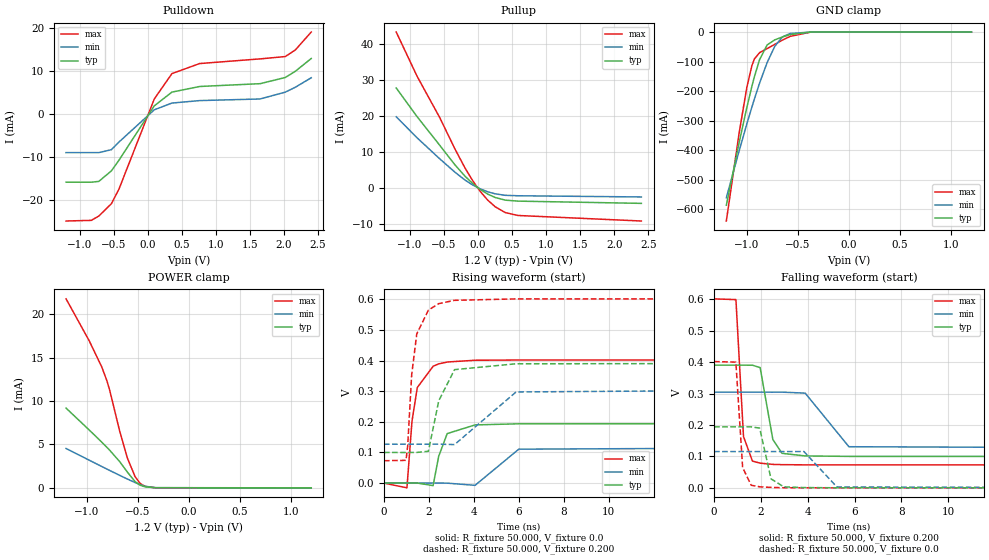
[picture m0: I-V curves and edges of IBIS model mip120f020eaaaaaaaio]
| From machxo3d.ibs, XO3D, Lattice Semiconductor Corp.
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|   Model mip120f020eaaaaaaaio
[Model] mip120f020eaaaaaaaio
Model_type I/O
Polarity   Non-Inverting
Enable   Active-Low
Vinl =  0.0V
Vinh =  0.400V
Vmeas =  0.200V
Cref =  3.000pF
Rref =  50.000
Vref =  0.200V
C_comp   4.200pF   3.800pF   7.500pF
[Temperature Range]   25.000   0.105k   -40.000
[Voltage Range]   1.200V   1.140V   1.260V
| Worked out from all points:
|   slope of the pulldown table from 0 to 0.18 V, typ, clamps not added: 55.1 ohm
|   slope of the pullup table from 0 to 0.18 V, typ, clamps not added: 85.3 ohm
|   GND clamp passes 1 mA (typ) near -0.44 V on its own axis
|   POWER clamp passes 1 mA (typ) near -0.55 V on its own axis
|   rising waveform, R_fixture 50.000, V_fixture 0.0: 20-80 % time 405ps typ, 576ps min, 395ps max; typ from 0 V to 0.194 V
|   rising waveform, R_fixture 50.000, V_fixture 0.200: 20-80 % time 466ps typ, 974ps min, 393ps max; typ from 0.1 V to 0.391 V
|   falling waveform, R_fixture 50.000, V_fixture 0.200: 20-80 % time 411ps typ, 886ps min, 199ps max; typ from 0.391 V to 0.1 V
|   falling waveform, R_fixture 50.000, V_fixture 0.0: 20-80 % time 331ps typ, 496ps min, 181ps max; typ from 0.194 V to 0 V
[Pulldown]
|Voltage   I(typ)   I(min)   I(max)
-1.2V     -15.77mA   -8.921mA   -24.76mA
-830mV    -15.77mA   -8.921mA   -24.61mA
-719mV    -15.58mA   -8.921mA   -23.61mA
-534mV    -13.14mA   -8.234mA   -20.74mA
-423mV    -10.67mA   -6.463mA   -17.35mA
95mV      1.91mA     997.3uA    3.496mA
354mV     5.095mA    2.558mA    9.38mA
761mV     6.397mA    3.131mA    11.71mA
1.649V    7.049mA    3.505mA    12.79mA
2.019V    8.479mA    5.088mA    13.33mA
2.167V    9.932mA    6.227mA    14.87mA
2.4V      12.88mA    8.418mA    19.01mA
[Pullup]
|Voltage   I(typ)   I(min)   I(max)
-1.2V     27.77mA    19.76mA    43.33mA
-893mV    19.78mA    13.89mA    31.01mA
-560mV    11.8mA     8.039mA    19.5mA
-338mV    6.396mA    4.353mA    10.82mA
-190mV    3.229mA    2.154mA    5.518mA
-79mV     1.223mA    799.3uA    2.039mA
32mV      -444uA     -284.1uA   -972.5uA
143mV     -1.752mA   -1.109mA   -3.419mA
254mV     -2.703mA   -1.688mA   -5.288mA
402mV     -3.439mA   -2.096mA   -6.902mA
587mV     -3.713mA   -2.22mA    -7.705mA
2.4V      -4.336mA   -2.552mA   -9.245mA
[GND_clamp]
|Voltage   I(typ)   I(min)   I(max)
-1.2V     -586.8mA   -561.6mA   -640.4mA
-1.075V   -375.3mA   -403.2mA   -342.9mA
-1V       -256.8mA   -312.3mA   -188.8mA
-950mV    -184.3mA   -254.5mA   -114.1mA
-925mV    -151.1mA   -226.6mA   -91.28mA
-875mV    -93.98mA   -173.6mA   -70.02mA
-800mV    -43.52mA   -102.9mA   -56.06mA
-725mV    -26.41mA   -48.03mA   -41.59mA
-650mV    -16.51mA   -16.35mA   -27.18mA
-575mV    -8.675mA   -5.014mA   -14.71mA
-375mV    -184.4uA   -82.53uA   -274.8uA
1.2V      0A         0A         0A
[POWER_clamp]
|Voltage   I(typ)   I(min)   I(max)
-1.2V     9.182mA    4.531mA    21.77mA
-975mV    6.681mA    3.195mA    16.97mA
-850mV    5.258mA    2.452mA    13.91mA
-800mV    4.664mA    2.159mA    12.32mA
-775mV    4.358mA    2.014mA    11.33mA
-675mV    3.018mA    1.438mA    6.528mA
-600mV    1.815mA    1.016mA    3.434mA
-525mV    718.8uA    613.1uA    1.299mA
-475mV    302.9uA    372.4uA    509.2uA
-425mV    111.3uA    180.4uA    160.1uA
-325mV    13.19uA    20.54uA    12.3uA
1.2V      0A         0A         3.813nA
[Ramp]
| variable   typ   min   max
dV/dt_r   0.117/0.429n   69.294m/0.573n   0.241/0.398n
dV/dt_f   0.196/0.410n   97.283m/0.584n   0.346/0.350n
R_load = 50.000
[Rising Waveform]
R_fixture= 50.000
V_fixture= 0.0
V_fixture_min= 0.0
V_fixture_max= 0.0
|time   V(typ)   V(min)   V(max)
0s        4.708nV    57.48nV    2.342nV
1.022ns   13.42uV    13.77uV    -15.58mV
1.246ns   188.3uV    13.77uV    202mV
1.483ns   75.1uV     13.77uV    312.2mV
2.185ns   -8.251mV   63.99uV    381.7mV
2.434ns   87.55mV    167uV      389.6mV
2.811ns   161.7mV    -217.7uV   395.6mV
4.05ns    190.1mV    -7.385mV   401.4mV
5.994ns   193.7mV    110.8mV    402.2mV
20ns      194.3mV    115.5mV    402.3mV
[Rising Waveform]
R_fixture= 50.000
V_fixture= 0.200
V_fixture_min= 0.191
V_fixture_max= 0.211
|time   V(typ)   V(min)   V(max)
0s        99.98mV    127mV      73.06mV
981ps     99.97mV    127mV      74.26mV
1.056ns   100mV      127mV      121.9mV
1.232ns   100.1mV    127mV      353.6mV
1.458ns   100.1mV    127mV      487mV
1.976ns   104mV      127mV      565.4mV
2.437ns   269.1mV    127.2mV    586.4mV
3.138ns   370.7mV    125.8mV    597.2mV
5.873ns   389.9mV    297.8mV    601.9mV
20ns      390.8mV    304.8mV    602mV
[Falling Waveform]
R_fixture= 50.000
V_fixture= 0.200
V_fixture_min= 0.191
V_fixture_max= 0.211
|time   V(typ)   V(min)   V(max)
0s        390.8mV    304.8mV    602mV
933ps     390.8mV    304.8mV    599.6mV
1.257ns   390.8mV    304.8mV    163.4mV
1.639ns   390.7mV    304.8mV    85.23mV
1.967ns   383mV      304.8mV    78.69mV
2.509ns   154.3mV    304.7mV    74.72mV
2.898ns   110mV      304.9mV    73.93mV
3.89ns    101.7mV    301.7mV    73.21mV
5.758ns   100.2mV    131mV      73.05mV
20ns      99.97mV    127mV      73.04mV
[Falling Waveform]
R_fixture= 50.000
V_fixture= 0.0
V_fixture_min= 0.0
V_fixture_max= 0.0
|time   V(typ)   V(min)   V(max)
0s        194.3mV    115.5mV    402.3mV
930ps     194.3mV    115.5mV    400.5mV
1.22ns    194.3mV    115.5mV    64.34mV
1.587ns   194.3mV    115.5mV    8.153mV
1.948ns   190.2mV    115.5mV    3.321mV
2.432ns   28.63mV    115.5mV    1.341mV
2.978ns   3.099mV    115.6mV    380.1uV
3.836ns   942.6uV    115.8mV    93.53uV
5.244ns   195.7uV    2.863mV    14.43uV
20ns      3.523nV    -297.3nV   -626.4nV
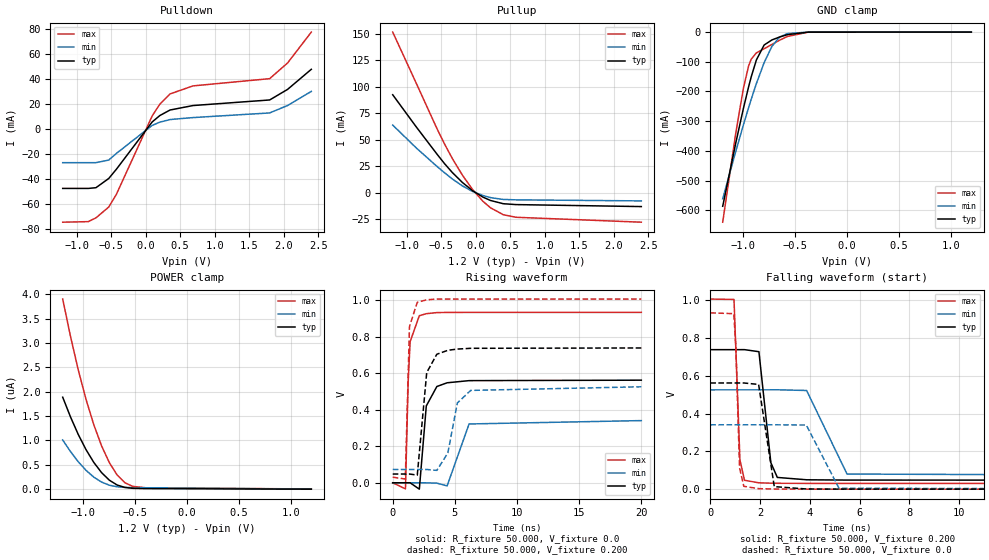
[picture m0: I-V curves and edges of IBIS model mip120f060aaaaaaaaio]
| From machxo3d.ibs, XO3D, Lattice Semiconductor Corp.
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|   Model mip120f060aaaaaaaaio
[Model] mip120f060aaaaaaaaio
Model_type I/O
Polarity   Non-Inverting
Enable   Active-Low
Vinl =  0.0V
Vinh =  0.400V
Vmeas =  0.200V
Cref =  3.000pF
Rref =  50.000
Vref =  0.200V
C_comp   4.200pF   3.800pF   7.500pF
[Temperature Range]   25.000   0.105k   -40.000
[Voltage Range]   1.200V   1.140V   1.260V
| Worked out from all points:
|   slope of the pulldown table from 0 to 0.18 V, typ, clamps not added: 18.4 ohm
|   slope of the pullup table from 0 to 0.18 V, typ, clamps not added: 28.4 ohm
|   GND clamp passes 1 mA (typ) near -0.44 V on its own axis
|   rising waveform, R_fixture 50.000, V_fixture 0.0: 20-80 % time 451ps typ, 631ps min, 245ps max; typ from 0 V to 0.561 V
|   rising waveform, R_fixture 50.000, V_fixture 0.200: 20-80 % time 457ps typ, 752ps min, 211ps max; typ from 0.048 V to 0.737 V
|   falling waveform, R_fixture 50.000, V_fixture 0.200: 20-80 % time 312ps typ, 749ps min, 121ps max; typ from 0.737 V to 0.048 V
|   falling waveform, R_fixture 50.000, V_fixture 0.0: 20-80 % time 281ps typ, 499ps min, 120ps max; typ from 0.561 V to 0 V
[Pulldown]
|Voltage   I(typ)   I(min)   I(max)
-1.2V     -47.32mA   -26.76mA   -74.28mA
-830mV    -47.32mA   -26.76mA   -73.83mA
-719mV    -46.75mA   -26.76mA   -70.83mA
-534mV    -39.41mA   -24.7mA    -62.22mA
-423mV    -32.02mA   -19.39mA   -52.05mA
95mV      5.729mA    2.992mA    10.49mA
206mV     10.86mA    5.583mA    19.95mA
354mV     15.29mA    7.674mA    28.14mA
687mV     18.86mA    9.24mA     34.55mA
1.797V    23.32mA    12.96mA    40.33mA
2.056V    31.75mA    18.89mA    52.83mA
2.4V      47.8mA     30.14mA    77.51mA
[Pullup]
|Voltage   I(typ)   I(min)   I(max)
-1.2V     92.48mA    63.86mA    151.6mA
-856mV    61.88mA    42.13mA    102.9mA
-560mV    36.58mA    24.92mA    60.65mA
-449mV    27.45mA    18.84mA    45.95mA
-338mV    19.21mA    13.09mA    32.49mA
-190mV    9.687mA    6.463mA    16.55mA
-42mV     1.884mA    1.222mA    2.939mA
106mV     -4.067mA   -2.584mA   -8.006mA
217mV     -7.275mA   -4.565mA   -14.19mA
402mV     -10.32mA   -6.287mA   -20.71mA
587mV     -11.14mA   -6.66mA    -23.11mA
2.4V      -13.01mA   -7.655mA   -27.74mA
[GND_clamp]
|Voltage   I(typ)   I(min)   I(max)
-1.2V     -586.8mA   -561.6mA   -640.4mA
-1.075V   -375.3mA   -403.2mA   -342.9mA
-1V       -256.8mA   -312.3mA   -188.8mA
-950mV    -184.3mA   -254.5mA   -114.1mA
-925mV    -151.1mA   -226.6mA   -91.28mA
-875mV    -93.98mA   -173.6mA   -70.02mA
-800mV    -43.52mA   -102.9mA   -56.06mA
-725mV    -26.41mA   -48.03mA   -41.59mA
-650mV    -16.51mA   -16.35mA   -27.18mA
-575mV    -8.675mA   -5.014mA   -14.71mA
-375mV    -184.4uA   -82.53uA   -274.8uA
1.2V      0A         0A         0A
[POWER_clamp]
|Voltage   I(typ)   I(min)   I(max)
-1.2V     1.889uA    1.011uA    3.905uA
-1.125V   1.485uA    772.5nA    3.141uA
-1.05V    1.124uA    563.1nA    2.451uA
-975mV    812.1nA    387.4nA    1.845uA
-900mV    550.1nA    247.5nA    1.324uA
-825mV    340.1nA    145.7nA    890.5nA
-750mV    184.9nA    81.62nA    545.5nA
-675mV    85.57nA    49.09nA    292.2nA
-600mV    35.85nA    35.97nA    132.8nA
-525mV    17.85nA    31.27nA    57.79nA
-400mV    11.64nA    28.61nA    28.94nA
1.2V      0A         0A         3.813nA
[Ramp]
| variable   typ   min   max
dV/dt_r   0.337/0.469n   0.204/0.622n   0.559/0.254n
dV/dt_f   0.483/0.344n   0.277/0.595n   0.628/0.160n
R_load = 50.000
[Rising Waveform]
R_fixture= 50.000
V_fixture= 0.0
V_fixture_min= 0.0
V_fixture_max= 0.0
|time   V(typ)   V(min)   V(max)
0s        2.29nV     33nV       1nV
1.027ns   20.68uV    5.828uV    -33.43mV
1.242ns   85.89uV    5.828uV    548.8mV
1.402ns   -122.3uV   5.828uV    772.2mV
2.142ns   -34.95mV   30.65uV    914mV
2.702ns   420.4mV    -249.7uV   925mV
3.553ns   526.7mV    -2.113mV   931mV
4.377ns   547mV      -17mV      931.9mV
6.143ns   558.8mV    321.7mV    932.2mV
20ns      561.3mV    340.2mV    932.2mV
[Rising Waveform]
R_fixture= 50.000
V_fixture= 0.200
V_fixture_min= 0.191
V_fixture_max= 0.211
|time   V(typ)   V(min)   V(max)
0s        47.81mV    72.89mV    30.45mV
1.013ns   47.81mV    72.91mV    20.5mV
1.349ns   47.86mV    72.91mV    854.6mV
1.977ns   41.96mV    72.89mV    987.2mV
2.736ns   602.9mV    72.82mV    1.001V
3.549ns   703.1mV    67.78mV    1.005V
4.439ns   724.8mV    163.5mV    1.005V
5.197ns   731.4mV    436.3mV    1.005V
6.275ns   735.6mV    505.3mV    1.005V
20ns      737.5mV    525.1mV    1.005V
[Falling Waveform]
R_fixture= 50.000
V_fixture= 0.200
V_fixture_min= 0.191
V_fixture_max= 0.211
|time   V(typ)   V(min)   V(max)
0s        737.5mV    525.1mV    1.005V
953ps     737.5mV    525.2mV    1.003V
1.191ns   737.5mV    525.2mV    155.2mV
1.375ns   737.6mV    525.2mV    46.92mV
1.954ns   726.7mV    525.2mV    33.65mV
2.433ns   140.3mV    525.2mV    31.68mV
2.693ns   62.06mV    525.4mV    31.06mV
3.87ns    49.6mV     521.7mV    30.52mV
5.493ns   48.03mV    79.96mV    30.45mV
20ns      47.8mV     72.89mV    30.44mV
[Falling Waveform]
R_fixture= 50.000
V_fixture= 0.0
V_fixture_min= 0.0
V_fixture_max= 0.0
|time   V(typ)   V(min)   V(max)
0s        561.3mV    340.2mV    932.2mV
945ps     561.4mV    340.3mV    927.7mV
1.028ns   561.4mV    340.3mV    753.2mV
1.175ns   561.4mV    340.3mV    112.9mV
1.347ns   561.4mV    340.3mV    15.19mV
1.942ns   553.7mV    340.3mV    2.73mV
2.571ns   13.51mV    340.3mV    769.1uV
3.855ns   1.089mV    339.1mV    61.15uV
5.171ns   255.6uV    5.066mV    24.05uV
20ns      -442.6nV   -793.9nV   -429.1nV
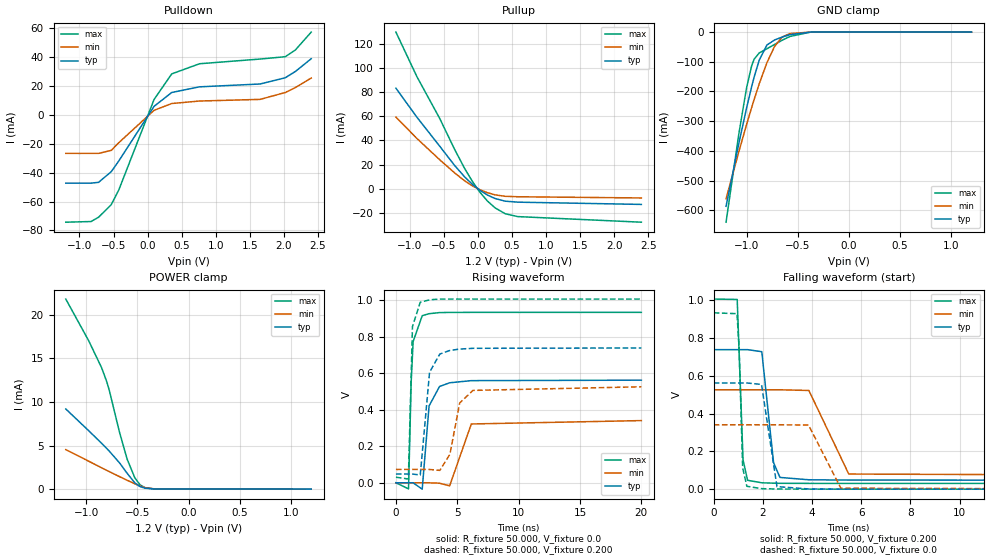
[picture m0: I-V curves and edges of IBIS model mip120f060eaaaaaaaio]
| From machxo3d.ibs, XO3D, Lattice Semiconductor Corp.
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|   Model mip120f060eaaaaaaaio
[Model] mip120f060eaaaaaaaio
Model_type I/O
Polarity   Non-Inverting
Enable   Active-Low
Vinl =  0.0V
Vinh =  0.400V
Vmeas =  0.200V
Cref =  3.000pF
Rref =  50.000
Vref =  0.200V
C_comp   4.200pF   3.800pF   7.500pF
[Temperature Range]   25.000   0.105k   -40.000
[Voltage Range]   1.200V   1.140V   1.260V
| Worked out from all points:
|   slope of the pulldown table from 0 to 0.18 V, typ, clamps not added: 18.4 ohm
|   slope of the pullup table from 0 to 0.18 V, typ, clamps not added: 28.4 ohm
|   GND clamp passes 1 mA (typ) near -0.44 V on its own axis
|   POWER clamp passes 1 mA (typ) near -0.55 V on its own axis
|   rising waveform, R_fixture 50.000, V_fixture 0.0: 20-80 % time 451ps typ, 631ps min, 245ps max; typ from 0 V to 0.561 V
|   rising waveform, R_fixture 50.000, V_fixture 0.200: 20-80 % time 456ps typ, 763ps min, 211ps max; typ from 0.048 V to 0.737 V
|   falling waveform, R_fixture 50.000, V_fixture 0.200: 20-80 % time 312ps typ, 749ps min, 121ps max; typ from 0.737 V to 0.048 V
|   falling waveform, R_fixture 50.000, V_fixture 0.0: 20-80 % time 281ps typ, 499ps min, 120ps max; typ from 0.561 V to 0 V
[Pulldown]
|Voltage   I(typ)   I(min)   I(max)
-1.2V     -47.32mA   -26.76mA   -74.28mA
-830mV    -47.32mA   -26.76mA   -73.83mA
-719mV    -46.75mA   -26.76mA   -70.83mA
-534mV    -39.41mA   -24.7mA    -62.22mA
-423mV    -32.02mA   -19.39mA   -52.05mA
95mV      5.729mA    2.992mA    10.49mA
354mV     15.29mA    7.674mA    28.14mA
761mV     19.19mA    9.392mA    35.13mA
1.649V    21.15mA    10.52mA    38.38mA
2.019V    25.44mA    15.26mA    39.99mA
2.167V    29.79mA    18.68mA    44.62mA
2.4V      38.62mA    25.27mA    57mA
[Pullup]
|Voltage   I(typ)   I(min)   I(max)
-1.2V     83.3mA     59.33mA    129.8mA
-893mV    59.32mA    41.69mA    92.95mA
-560mV    35.41mA    24.12mA    58.49mA
-338mV    19.19mA    13.06mA    32.47mA
-190mV    9.687mA    6.463mA    16.55mA
-79mV     3.668mA    2.398mA    6.116mA
32mV      -1.332mA   -852.4uA   -2.917mA
143mV     -5.255mA   -3.327mA   -10.26mA
254mV     -8.11mA    -5.063mA   -15.86mA
402mV     -10.32mA   -6.287mA   -20.71mA
587mV     -11.14mA   -6.66mA    -23.11mA
2.4V      -13.01mA   -7.655mA   -27.74mA
[GND_clamp]
|Voltage   I(typ)   I(min)   I(max)
-1.2V     -586.8mA   -561.6mA   -640.4mA
-1.075V   -375.3mA   -403.2mA   -342.9mA
-1V       -256.8mA   -312.3mA   -188.8mA
-950mV    -184.3mA   -254.5mA   -114.1mA
-925mV    -151.1mA   -226.6mA   -91.28mA
-875mV    -93.98mA   -173.6mA   -70.02mA
-800mV    -43.52mA   -102.9mA   -56.06mA
-725mV    -26.41mA   -48.03mA   -41.59mA
-650mV    -16.51mA   -16.35mA   -27.18mA
-575mV    -8.675mA   -5.014mA   -14.71mA
-375mV    -184.4uA   -82.53uA   -274.8uA
1.2V      0A         0A         0A
[POWER_clamp]
|Voltage   I(typ)   I(min)   I(max)
-1.2V     9.182mA    4.531mA    21.77mA
-975mV    6.681mA    3.195mA    16.97mA
-850mV    5.258mA    2.452mA    13.91mA
-800mV    4.664mA    2.159mA    12.32mA
-775mV    4.358mA    2.014mA    11.33mA
-675mV    3.018mA    1.438mA    6.528mA
-600mV    1.815mA    1.016mA    3.434mA
-525mV    718.8uA    613.1uA    1.299mA
-475mV    302.9uA    372.4uA    509.2uA
-425mV    111.3uA    180.4uA    160.1uA
-325mV    13.19uA    20.54uA    12.3uA
1.2V      0A         0A         3.813nA
[Ramp]
| variable   typ   min   max
dV/dt_r   0.337/0.469n   0.204/0.622n   0.559/0.254n
dV/dt_f   0.483/0.344n   0.277/0.595n   0.628/0.160n
R_load = 50.000
[Rising Waveform]
R_fixture= 50.000
V_fixture= 0.0
V_fixture_min= 0.0
V_fixture_max= 0.0
|time   V(typ)   V(min)   V(max)
0s        2.29nV     33nV       1nV
1.027ns   20.68uV    5.829uV    -33.43mV
1.242ns   85.88uV    5.829uV    548.8mV
1.402ns   -122.2uV   5.829uV    772.3mV
2.142ns   -34.95mV   30.65uV    914mV
2.702ns   420.4mV    -249.7uV   925mV
3.553ns   526.7mV    -2.113mV   931mV
4.377ns   547mV      -17mV      931.9mV
6.143ns   558.8mV    321.7mV    932.2mV
20ns      561.3mV    340.2mV    932.2mV
[Rising Waveform]
R_fixture= 50.000
V_fixture= 0.200
V_fixture_min= 0.191
V_fixture_max= 0.211
|time   V(typ)   V(min)   V(max)
0s        47.81mV    72.89mV    30.45mV
1.013ns   47.81mV    72.91mV    20.5mV
1.349ns   47.86mV    72.91mV    854.6mV
1.983ns   42.33mV    72.89mV    987.4mV
2.742ns   604.9mV    72.82mV    1.001V
3.577ns   704.2mV    67.77mV    1.005V
4.397ns   724mV      155.4mV    1.005V
5.197ns   731.4mV    436.3mV    1.005V
6.275ns   735.6mV    505.3mV    1.005V
20ns      737.5mV    525.1mV    1.005V
[Falling Waveform]
R_fixture= 50.000
V_fixture= 0.200
V_fixture_min= 0.191
V_fixture_max= 0.211
|time   V(typ)   V(min)   V(max)
0s        737.5mV    525.1mV    1.005V
953ps     737.5mV    525.2mV    1.003V
1.191ns   737.5mV    525.2mV    155.2mV
1.375ns   737.6mV    525.2mV    46.92mV
1.954ns   726.7mV    525.2mV    33.65mV
2.433ns   140.3mV    525.2mV    31.68mV
2.693ns   62.06mV    525.4mV    31.06mV
3.87ns    49.6mV     521.7mV    30.52mV
5.493ns   48.03mV    79.96mV    30.45mV
20ns      47.8mV     72.89mV    30.44mV
[Falling Waveform]
R_fixture= 50.000
V_fixture= 0.0
V_fixture_min= 0.0
V_fixture_max= 0.0
|time   V(typ)   V(min)   V(max)
0s        561.3mV    340.2mV    932.2mV
945ps     561.4mV    340.3mV    927.7mV
1.028ns   561.4mV    340.3mV    753.2mV
1.175ns   561.4mV    340.3mV    112.9mV
1.347ns   561.4mV    340.3mV    15.19mV
1.942ns   553.7mV    340.3mV    2.73mV
2.571ns   13.51mV    340.3mV    769.1uV
3.855ns   1.089mV    339.1mV    61.15uV
5.171ns   255.6uV    5.066mV    24.05uV
20ns      -442.6nV   -793.9nV   -429.1nV
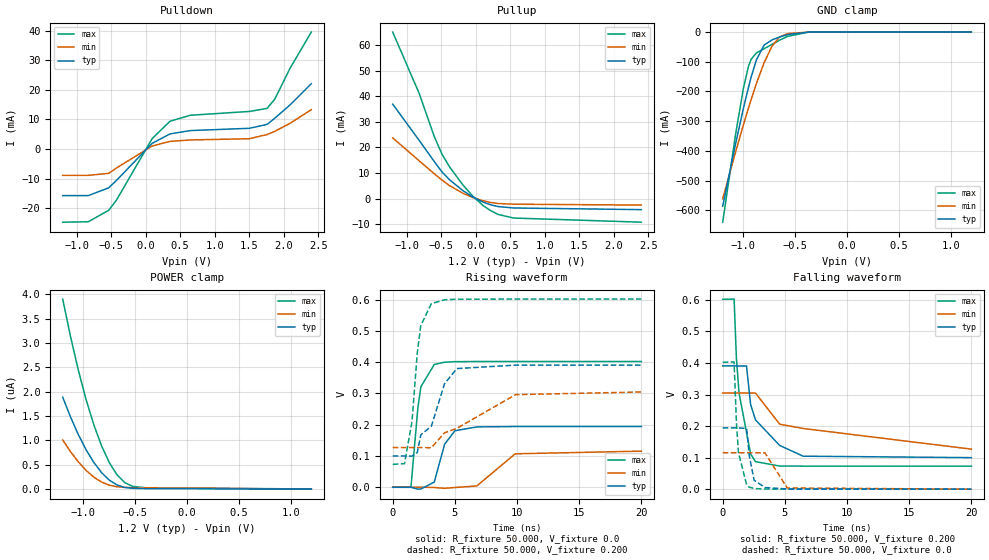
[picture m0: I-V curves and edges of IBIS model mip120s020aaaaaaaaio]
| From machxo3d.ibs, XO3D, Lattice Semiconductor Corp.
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|   Model mip120s020aaaaaaaaio
[Model] mip120s020aaaaaaaaio
Model_type I/O
Polarity   Non-Inverting
Enable   Active-Low
Vinl =  0.0V
Vinh =  0.400V
Vmeas =  0.200V
Cref =  3.000pF
Rref =  50.000
Vref =  0.200V
C_comp   4.200pF   3.800pF   7.500pF
[Temperature Range]   25.000   0.105k   -40.000
[Voltage Range]   1.200V   1.140V   1.260V
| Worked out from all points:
|   slope of the pulldown table from 0 to 0.18 V, typ, clamps not added: 55.1 ohm
|   slope of the pullup table from 0 to 0.18 V, typ, clamps not added: 85.3 ohm
|   GND clamp passes 1 mA (typ) near -0.44 V on its own axis
|   rising waveform, R_fixture 50.000, V_fixture 0.0: 20-80 % time 915ps typ, 1.63ns min, 579ps max; typ from 0 V to 0.194 V
|   rising waveform, R_fixture 50.000, V_fixture 0.200: 20-80 % time 1.99ns typ, 4.51ns min, 797ps max; typ from 0.1 V to 0.391 V
|   falling waveform, R_fixture 50.000, V_fixture 0.200: 20-80 % time 2.19ns typ, 4.67ns min, 892ps max; typ from 0.391 V to 0.1 V
|   falling waveform, R_fixture 50.000, V_fixture 0.0: 20-80 % time 395ps typ, 462ps min, 380ps max; typ from 0.194 V to 0 V
[Pulldown]
|Voltage   I(typ)   I(min)   I(max)
-1.2V     -15.77mA   -8.921mA   -24.76mA
-830mV    -15.77mA   -8.921mA   -24.61mA
-534mV    -13.14mA   -8.234mA   -20.74mA
-423mV    -10.67mA   -6.463mA   -17.35mA
95mV      1.91mA     997.3uA    3.496mA
354mV     5.095mA    2.558mA    9.38mA
650mV     6.221mA    3.05mA     11.4mA
1.501V    6.983mA    3.464mA    12.68mA
1.76V     8.299mA    4.874mA    13.72mA
1.871V    10.4mA     5.962mA    16.85mA
2.093V    14.92mA    8.691mA    27.32mA
2.4V      22.06mA    13.29mA    39.52mA
[Pullup]
|Voltage   I(typ)   I(min)   I(max)
-1.2V     36.91mA    23.72mA    65.09mA
-819mV    22.83mA    14.81mA    41.27mA
-597mV    14.43mA    9.66mA     24.15mA
-486mV    10.38mA    7.228mA    17.33mA
-375mV    7.309mA    5.026mA    12.31mA
-190mV    3.229mA    2.154mA    5.518mA
-42mV     628.1uA    407.3uA    979.6uA
106mV     -1.356mA   -861.5uA   -2.669mA
217mV     -2.425mA   -1.522mA   -4.729mA
328mV     -3.145mA   -1.941mA   -6.218mA
550mV     -3.688mA   -2.208mA   -7.621mA
2.4V      -4.336mA   -2.551mA   -9.245mA
[GND_clamp]
|Voltage   I(typ)   I(min)   I(max)
-1.2V     -586.8mA   -561.6mA   -640.4mA
-1.075V   -375.3mA   -403.2mA   -342.9mA
-1V       -256.8mA   -312.3mA   -188.8mA
-950mV    -184.3mA   -254.5mA   -114.1mA
-925mV    -151.1mA   -226.6mA   -91.28mA
-875mV    -93.98mA   -173.6mA   -70.02mA
-800mV    -43.52mA   -102.9mA   -56.06mA
-725mV    -26.41mA   -48.03mA   -41.59mA
-650mV    -16.51mA   -16.35mA   -27.18mA
-575mV    -8.675mA   -5.014mA   -14.71mA
-375mV    -184.4uA   -82.53uA   -274.8uA
1.2V      0A         0A         0A
[POWER_clamp]
|Voltage   I(typ)   I(min)   I(max)
-1.2V     1.889uA    1.011uA    3.905uA
-1.125V   1.485uA    772.5nA    3.141uA
-1.05V    1.124uA    563.1nA    2.451uA
-975mV    812.1nA    387.4nA    1.845uA
-900mV    550nA      247.6nA    1.324uA
-825mV    340.1nA    145.7nA    890.5nA
-750mV    184.8nA    81.65nA    545.5nA
-675mV    85.56nA    49.12nA    292.1nA
-600mV    35.84nA    36nA       132.7nA
-525mV    17.84nA    31.3nA     57.76nA
-400mV    11.63nA    28.64nA    28.92nA
1.2V      0A         0A         3.813nA
[Ramp]
| variable   typ   min   max
dV/dt_r   0.117/0.892n   69.290m/1.667n   0.241/0.586n
dV/dt_f   0.196/1.789n   97.146m/3.072n   0.346/0.972n
R_load = 50.000
[Rising Waveform]
R_fixture= 50.000
V_fixture= 0.0
V_fixture_min= 0.0
V_fixture_max= 0.0
|time   V(typ)   V(min)   V(max)
0s        4.708nV    57.48nV    2.342nV
1.467ns   90.66uV    13.48uV    -233.5uV
2.026ns   -6.137mV   66.77uV    254.5mV
2.269ns   -5.478mV   195.4uV    321.7mV
3.345ns   16.61mV    -767.7uV   392.9mV
4.175ns   137.4mV    -3.391mV   400mV
5.005ns   180.8mV    -859.1uV   401.7mV
6.771ns   193mV      4.271mV    402.2mV
9.856ns   194.2mV    107mV      402.3mV
20ns      194.3mV    115.5mV    402.3mV
[Rising Waveform]
R_fixture= 50.000
V_fixture= 0.200
V_fixture_min= 0.191
V_fixture_max= 0.211
|time   V(typ)   V(min)   V(max)
0s        99.98mV    127mV      73.06mV
951ps     99.97mV    127mV      75.54mV
1.555ns   99.52mV    127mV      211.2mV
1.975ns   111mV      127mV      429.6mV
2.259ns   167.6mV    127mV      517.1mV
3.109ns   195.3mV    126.4mV    587.3mV
4.171ns   331.5mV    174.1mV    599.6mV
5.159ns   379.6mV    188.4mV    601.6mV
9.882ns   390.7mV    296.2mV    602mV
20ns      390.8mV    304.8mV    602mV
[Falling Waveform]
R_fixture= 50.000
V_fixture= 0.200
V_fixture_min= 0.191
V_fixture_max= 0.211
|time   V(typ)   V(min)   V(max)
0s        390.8mV    304.8mV    602mV
918ps     390.8mV    304.8mV    602.8mV
1.102ns   390.8mV    304.8mV    415.6mV
1.313ns   390.7mV    304.8mV    305.4mV
1.915ns   390.7mV    304.8mV    179.8mV
2.246ns   268.3mV    304.8mV    111.5mV
2.637ns   219.8mV    304.7mV    87.3mV
4.584ns   138.6mV    206mV      73.34mV
6.474ns   104.6mV    192.4mV    73.06mV
20ns      99.98mV    127mV      73.04mV
[Falling Waveform]
R_fixture= 50.000
V_fixture= 0.0
V_fixture_min= 0.0
V_fixture_max= 0.0
|time   V(typ)   V(min)   V(max)
0s        194.3mV    115.5mV    402.3mV
915ps     194.3mV    115.5mV    403.6mV
1.109ns   194.3mV    115.5mV    206.4mV
1.266ns   194.3mV    115.5mV    115.9mV
1.926ns   192.4mV    115.5mV    13.96mV
2.129ns   107.7mV    115.5mV    6.357mV
2.531ns   28.28mV    115.4mV    2.13mV
3.397ns   5.221mV    115.1mV    386.9uV
5.192ns   606.5uV    3.815mV    15.25uV
20ns      12.54nV    909.9nV    3.115nV
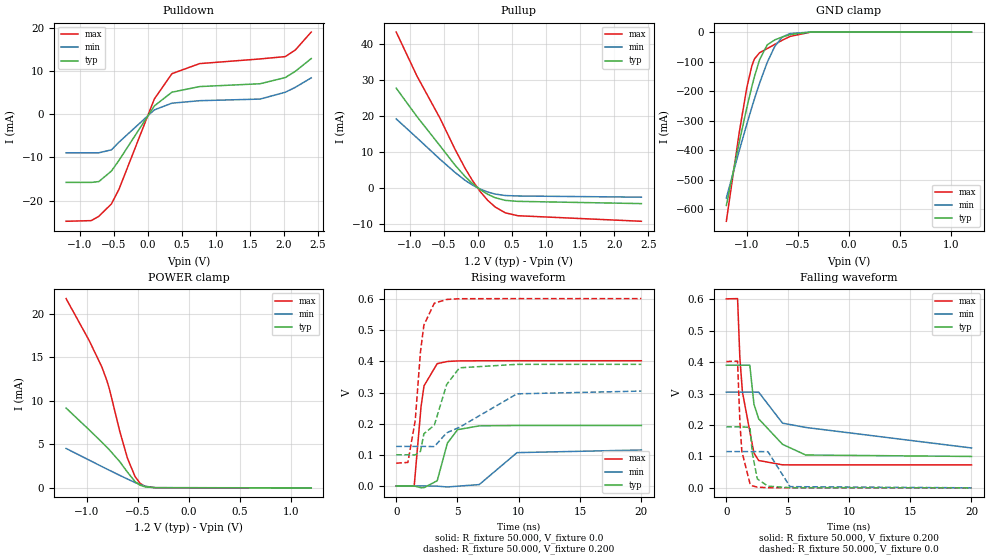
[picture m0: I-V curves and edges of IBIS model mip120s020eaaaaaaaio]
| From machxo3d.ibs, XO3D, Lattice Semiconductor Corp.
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|   Model mip120s020eaaaaaaaio
[Model] mip120s020eaaaaaaaio
Model_type I/O
Polarity   Non-Inverting
Enable   Active-Low
Vinl =  0.0V
Vinh =  0.400V
Vmeas =  0.200V
Cref =  3.000pF
Rref =  50.000
Vref =  0.200V
C_comp   4.200pF   3.800pF   7.500pF
[Temperature Range]   25.000   0.105k   -40.000
[Voltage Range]   1.200V   1.140V   1.260V
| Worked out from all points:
|   slope of the pulldown table from 0 to 0.18 V, typ, clamps not added: 55.1 ohm
|   slope of the pullup table from 0 to 0.18 V, typ, clamps not added: 85.3 ohm
|   GND clamp passes 1 mA (typ) near -0.44 V on its own axis
|   POWER clamp passes 1 mA (typ) near -0.55 V on its own axis
|   rising waveform, R_fixture 50.000, V_fixture 0.0: 20-80 % time 915ps typ, 1.63ns min, 579ps max; typ from 0 V to 0.194 V
|   rising waveform, R_fixture 50.000, V_fixture 0.200: 20-80 % time 1.99ns typ, 4.5ns min, 797ps max; typ from 0.1 V to 0.391 V
|   falling waveform, R_fixture 50.000, V_fixture 0.200: 20-80 % time 2.19ns typ, 4.67ns min, 892ps max; typ from 0.391 V to 0.1 V
|   falling waveform, R_fixture 50.000, V_fixture 0.0: 20-80 % time 395ps typ, 462ps min, 380ps max; typ from 0.194 V to 0 V
[Pulldown]
|Voltage   I(typ)   I(min)   I(max)
-1.2V     -15.77mA   -8.921mA   -24.76mA
-830mV    -15.77mA   -8.921mA   -24.61mA
-719mV    -15.58mA   -8.921mA   -23.61mA
-534mV    -13.14mA   -8.234mA   -20.74mA
-423mV    -10.67mA   -6.463mA   -17.35mA
95mV      1.91mA     997.3uA    3.496mA
354mV     5.095mA    2.558mA    9.38mA
761mV     6.397mA    3.131mA    11.71mA
1.649V    7.049mA    3.505mA    12.79mA
2.019V    8.479mA    5.088mA    13.33mA
2.167V    9.932mA    6.226mA    14.87mA
2.4V      12.88mA    8.416mA    19.01mA
[Pullup]
|Voltage   I(typ)   I(min)   I(max)
-1.2V     27.73mA    19.19mA    43.32mA
-893mV    19.78mA    13.89mA    31.01mA
-560mV    11.8mA     8.039mA    19.5mA
-338mV    6.396mA    4.353mA    10.82mA
-190mV    3.229mA    2.154mA    5.518mA
-79mV     1.223mA    799.3uA    2.039mA
32mV      -444uA     -284.1uA   -972.5uA
143mV     -1.752mA   -1.109mA   -3.419mA
254mV     -2.703mA   -1.688mA   -5.288mA
402mV     -3.439mA   -2.096mA   -6.902mA
587mV     -3.713mA   -2.22mA    -7.705mA
2.4V      -4.336mA   -2.551mA   -9.245mA
[GND_clamp]
|Voltage   I(typ)   I(min)   I(max)
-1.2V     -586.8mA   -561.6mA   -640.4mA
-1.075V   -375.3mA   -403.2mA   -342.9mA
-1V       -256.8mA   -312.3mA   -188.8mA
-950mV    -184.3mA   -254.5mA   -114.1mA
-925mV    -151.1mA   -226.6mA   -91.28mA
-875mV    -93.98mA   -173.6mA   -70.02mA
-800mV    -43.52mA   -102.9mA   -56.06mA
-725mV    -26.41mA   -48.03mA   -41.59mA
-650mV    -16.51mA   -16.35mA   -27.18mA
-575mV    -8.675mA   -5.014mA   -14.71mA
-375mV    -184.4uA   -82.53uA   -274.8uA
1.2V      0A         0A         0A
[POWER_clamp]
|Voltage   I(typ)   I(min)   I(max)
-1.2V     9.182mA    4.531mA    21.77mA
-975mV    6.681mA    3.195mA    16.97mA
-850mV    5.258mA    2.452mA    13.91mA
-800mV    4.664mA    2.159mA    12.32mA
-775mV    4.358mA    2.014mA    11.33mA
-675mV    3.018mA    1.438mA    6.528mA
-600mV    1.815mA    1.016mA    3.434mA
-525mV    718.8uA    613.1uA    1.299mA
-475mV    302.9uA    372.4uA    509.2uA
-425mV    111.3uA    180.4uA    160.1uA
-325mV    13.19uA    20.54uA    12.3uA
1.2V      0A         0A         3.813nA
[Ramp]
| variable   typ   min   max
dV/dt_r   0.117/0.892n   69.290m/1.667n   0.241/0.586n
dV/dt_f   0.196/1.789n   97.146m/3.072n   0.346/0.972n
R_load = 50.000
[Rising Waveform]
R_fixture= 50.000
V_fixture= 0.0
V_fixture_min= 0.0
V_fixture_max= 0.0
|time   V(typ)   V(min)   V(max)
0s        4.708nV    57.48nV    2.342nV
1.467ns   90.67uV    13.47uV    -233.6uV
2.026ns   -6.137mV   66.77uV    254.5mV
2.269ns   -5.478mV   195.4uV    321.7mV
3.345ns   16.61mV    -742.8uV   392.9mV
4.175ns   137.4mV    -3.391mV   400mV
5.005ns   180.8mV    -859.5uV   401.7mV
6.771ns   193mV      4.271mV    402.2mV
9.856ns   194.2mV    107mV      402.3mV
20ns      194.3mV    115.5mV    402.3mV
[Rising Waveform]
R_fixture= 50.000
V_fixture= 0.200
V_fixture_min= 0.191
V_fixture_max= 0.211
|time   V(typ)   V(min)   V(max)
0s        99.98mV    127mV      73.06mV
951ps     99.97mV    127mV      75.54mV
1.555ns   99.52mV    127mV      211.2mV
1.975ns   111mV      127mV      429.6mV
2.259ns   167.6mV    127mV      517.1mV
3.111ns   195.3mV    126.4mV    587.3mV
4.113ns   325.5mV    170.6mV    599.2mV
5.16ns    379.6mV    188.4mV    601.6mV
9.85ns    390.7mV    295.9mV    602mV
20ns      390.8mV    304.8mV    602mV
[Falling Waveform]
R_fixture= 50.000
V_fixture= 0.200
V_fixture_min= 0.191
V_fixture_max= 0.211
|time   V(typ)   V(min)   V(max)
0s        390.8mV    304.8mV    602mV
918ps     390.8mV    304.8mV    602.8mV
1.102ns   390.8mV    304.8mV    415.6mV
1.313ns   390.7mV    304.8mV    305.4mV
1.915ns   390.7mV    304.8mV    179.8mV
2.253ns   266.6mV    304.8mV    110.8mV
2.639ns   219.8mV    304.7mV    87.07mV
4.584ns   138.6mV    206mV      73.34mV
6.474ns   104.6mV    192.4mV    73.06mV
20ns      99.98mV    127mV      73.04mV
[Falling Waveform]
R_fixture= 50.000
V_fixture= 0.0
V_fixture_min= 0.0
V_fixture_max= 0.0
|time   V(typ)   V(min)   V(max)
0s        194.3mV    115.5mV    402.3mV
915ps     194.3mV    115.5mV    403.6mV
1.109ns   194.3mV    115.5mV    206.4mV
1.266ns   194.3mV    115.5mV    115.9mV
1.926ns   192.4mV    115.5mV    13.96mV
2.129ns   107.7mV    115.5mV    6.357mV
2.531ns   28.28mV    115.4mV    2.13mV
3.397ns   5.221mV    115.1mV    386.9uV
5.195ns   606.5uV    3.796mV    15.25uV
20ns      12.54nV    909.9nV    3.115nV
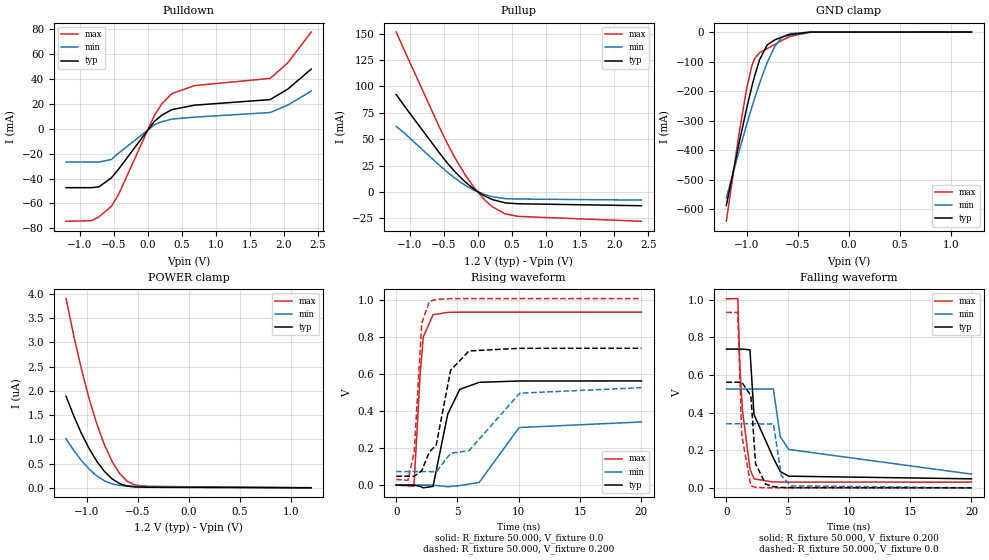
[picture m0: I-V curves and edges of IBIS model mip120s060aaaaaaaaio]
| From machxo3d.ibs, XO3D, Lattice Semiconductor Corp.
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|   Model mip120s060aaaaaaaaio
[Model] mip120s060aaaaaaaaio
Model_type I/O
Polarity   Non-Inverting
Enable   Active-Low
Vinl =  0.0V
Vinh =  0.400V
Vmeas =  0.200V
Cref =  3.000pF
Rref =  50.000
Vref =  0.200V
C_comp   4.200pF   3.800pF   7.500pF
[Temperature Range]   25.000   0.105k   -40.000
[Voltage Range]   1.200V   1.140V   1.260V
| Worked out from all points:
|   slope of the pulldown table from 0 to 0.18 V, typ, clamps not added: 18.4 ohm
|   slope of the pullup table from 0 to 0.18 V, typ, clamps not added: 28.4 ohm
|   GND clamp passes 1 mA (typ) near -0.44 V on its own axis
|   rising waveform, R_fixture 50.000, V_fixture 0.0: 20-80 % time 1.03ns typ, 1.88ns min, 470ps max; typ from 0 V to 0.561 V
|   rising waveform, R_fixture 50.000, V_fixture 0.200: 20-80 % time 1.33ns typ, 4.53ns min, 460ps max; typ from 0.048 V to 0.737 V
|   falling waveform, R_fixture 50.000, V_fixture 0.200: 20-80 % time 1.6ns typ, 3.65ns min, 696ps max; typ from 0.737 V to 0.048 V
|   falling waveform, R_fixture 50.000, V_fixture 0.0: 20-80 % time 401ps typ, 468ps min, 381ps max; typ from 0.561 V to 0 V
[Pulldown]
|Voltage   I(typ)   I(min)   I(max)
-1.2V     -47.32mA   -26.76mA   -74.28mA
-830mV    -47.32mA   -26.76mA   -73.83mA
-719mV    -46.75mA   -26.76mA   -70.83mA
-534mV    -39.41mA   -24.7mA    -62.22mA
-423mV    -32.02mA   -19.39mA   -52.05mA
95mV      5.729mA    2.992mA    10.49mA
206mV     10.86mA    5.583mA    19.95mA
354mV     15.29mA    7.674mA    28.14mA
687mV     18.86mA    9.24mA     34.55mA
1.797V    23.32mA    12.96mA    40.33mA
2.056V    31.75mA    18.89mA    52.83mA
2.4V      47.8mA     30.13mA    77.51mA
[Pullup]
|Voltage   I(typ)   I(min)   I(max)
-1.2V     92.36mA    62.18mA    151.6mA
-1.078V   81.36mA    55.68mA    133.9mA
-560mV    36.58mA    24.92mA    60.65mA
-449mV    27.45mA    18.84mA    45.95mA
-338mV    19.21mA    13.09mA    32.49mA
-190mV    9.687mA    6.463mA    16.55mA
-42mV     1.884mA    1.222mA    2.939mA
106mV     -4.067mA   -2.584mA   -8.006mA
217mV     -7.275mA   -4.565mA   -14.19mA
402mV     -10.32mA   -6.287mA   -20.71mA
587mV     -11.14mA   -6.66mA    -23.11mA
2.4V      -13.01mA   -7.654mA   -27.74mA
[GND_clamp]
|Voltage   I(typ)   I(min)   I(max)
-1.2V     -586.8mA   -561.6mA   -640.4mA
-1.075V   -375.3mA   -403.2mA   -342.9mA
-1V       -256.8mA   -312.3mA   -188.8mA
-950mV    -184.3mA   -254.5mA   -114.1mA
-925mV    -151.1mA   -226.6mA   -91.28mA
-875mV    -93.98mA   -173.6mA   -70.02mA
-800mV    -43.52mA   -102.9mA   -56.06mA
-725mV    -26.41mA   -48.03mA   -41.59mA
-650mV    -16.51mA   -16.35mA   -27.18mA
-575mV    -8.675mA   -5.014mA   -14.71mA
-375mV    -184.4uA   -82.53uA   -274.8uA
1.2V      0A         0A         0A
[POWER_clamp]
|Voltage   I(typ)   I(min)   I(max)
-1.2V     1.889uA    1.011uA    3.905uA
-1.125V   1.485uA    772.5nA    3.141uA
-1.05V    1.124uA    563.1nA    2.451uA
-975mV    812.1nA    387.4nA    1.845uA
-900mV    550.1nA    247.6nA    1.324uA
-825mV    340.1nA    145.7nA    890.5nA
-750mV    184.9nA    81.64nA    545.5nA
-675mV    85.57nA    49.11nA    292.2nA
-600mV    35.85nA    35.99nA    132.8nA
-525mV    17.85nA    31.3nA     57.78nA
-400mV    11.64nA    28.63nA    28.93nA
1.2V      0A         0A         3.813nA
[Ramp]
| variable   typ   min   max
dV/dt_r   0.337/1.029n   0.204/1.849n   0.559/0.468n
dV/dt_f   0.483/1.581n   0.276/3.159n   0.628/0.576n
R_load = 50.000
[Rising Waveform]
R_fixture= 50.000
V_fixture= 0.0
V_fixture_min= 0.0
V_fixture_max= 0.0
|time   V(typ)   V(min)   V(max)
0s        2.29nV     33nV       1nV
1.446ns   -136.3uV   6.559uV    -5.769mV
1.959ns   -6.909mV   31.56uV    601.1mV
2.21ns    -14.67mV   31.56uV    798.9mV
3.006ns   -6.692mV   -314.9uV   918.3mV
4.201ns   382.3mV    -8.762mV   930.8mV
5.185ns   515.8mV    -2.571mV   932mV
6.774ns   553.8mV    14.59mV    932.2mV
10.03ns   561mV      310.2mV    932.2mV
20ns      561.3mV    340.2mV    932.2mV
[Rising Waveform]
R_fixture= 50.000
V_fixture= 0.200
V_fixture_min= 0.191
V_fixture_max= 0.211
|time   V(typ)   V(min)   V(max)
0s        47.81mV    72.89mV    30.45mV
958ps     47.8mV     72.91mV    25.83mV
1.47ns    47.47mV    72.89mV    179.7mV
2.079ns   77.44mV    72.91mV    872.4mV
2.708ns   179.4mV    72.7mV     989.3mV
3.264ns   215.2mV    71.68mV    1.001V
4.438ns   618.5mV    171.4mV    1.005V
5.939ns   723mV      185.8mV    1.005V
10.08ns   737.1mV    495.4mV    1.005V
20ns      737.5mV    525.1mV    1.005V
[Falling Waveform]
R_fixture= 50.000
V_fixture= 0.200
V_fixture_min= 0.191
V_fixture_max= 0.211
|time   V(typ)   V(min)   V(max)
0s        737.5mV    525.1mV    1.005V
935ps     737.5mV    525.2mV    1.006V
1.115ns   737.5mV    525.2mV    631.9mV
1.312ns   737.5mV    525.2mV    414.2mV
1.926ns   733.7mV    525.2mV    100.7mV
2.257ns   389.7mV    525.2mV    47.83mV
3.838ns   158.8mV    525.7mV    30.97mV
4.401ns   86.47mV    271.7mV    30.64mV
5.087ns   61.95mV    204.1mV    30.5mV
20ns      47.8mV     72.91mV    30.44mV
[Falling Waveform]
R_fixture= 50.000
V_fixture= 0.0
V_fixture_min= 0.0
V_fixture_max= 0.0
|time   V(typ)   V(min)   V(max)
0s        561.3mV    340.2mV    932.2mV
927ps     561.4mV    340.3mV    933mV
1.263ns   561.3mV    340.3mV    277.6mV
2ns       490.4mV    340.3mV    9.923mV
2.387ns   127.6mV    340.3mV    2.856mV
3.207ns   19.65mV    339.3mV    409.8uV
3.843ns   6.28mV     340.3mV    107.6uV
4.479ns   2.104mV    66.35mV    52.42uV
5.251ns   729.5uV    10.51mV    18.83uV
20ns      6.126nV    1.109uV    15.51nV
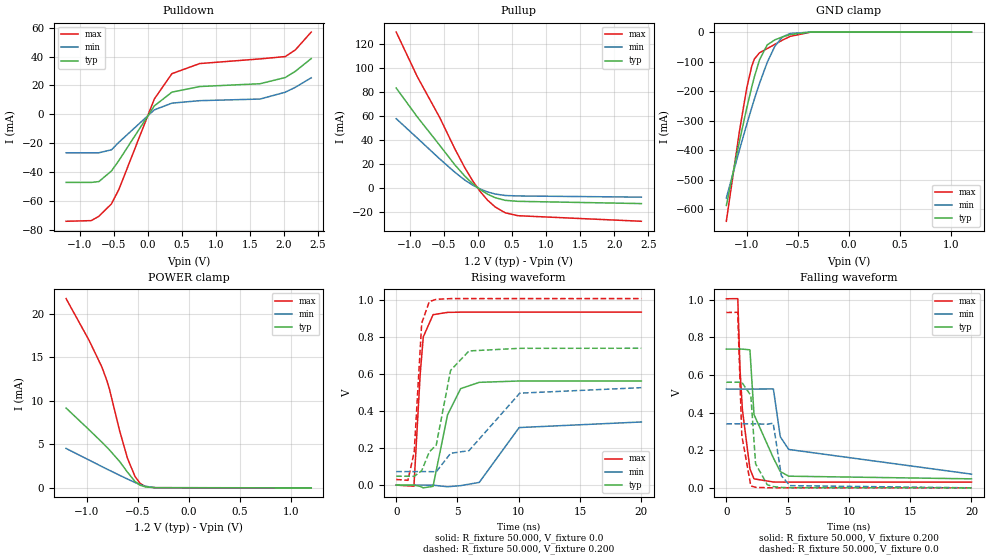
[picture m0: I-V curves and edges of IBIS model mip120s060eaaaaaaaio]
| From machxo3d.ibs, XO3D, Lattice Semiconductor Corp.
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|   Model mip120s060eaaaaaaaio
[Model] mip120s060eaaaaaaaio
Model_type I/O
Polarity   Non-Inverting
Enable   Active-Low
Vinl =  0.0V
Vinh =  0.400V
Vmeas =  0.200V
Cref =  3.000pF
Rref =  50.000
Vref =  0.200V
C_comp   4.200pF   3.800pF   7.500pF
[Temperature Range]   25.000   0.105k   -40.000
[Voltage Range]   1.200V   1.140V   1.260V
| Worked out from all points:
|   slope of the pulldown table from 0 to 0.18 V, typ, clamps not added: 18.4 ohm
|   slope of the pullup table from 0 to 0.18 V, typ, clamps not added: 28.4 ohm
|   GND clamp passes 1 mA (typ) near -0.44 V on its own axis
|   POWER clamp passes 1 mA (typ) near -0.55 V on its own axis
|   rising waveform, R_fixture 50.000, V_fixture 0.0: 20-80 % time 1.03ns typ, 1.88ns min, 470ps max; typ from 0 V to 0.561 V
|   rising waveform, R_fixture 50.000, V_fixture 0.200: 20-80 % time 1.33ns typ, 4.53ns min, 460ps max; typ from 0.048 V to 0.737 V
|   falling waveform, R_fixture 50.000, V_fixture 0.200: 20-80 % time 1.6ns typ, 3.65ns min, 696ps max; typ from 0.737 V to 0.048 V
|   falling waveform, R_fixture 50.000, V_fixture 0.0: 20-80 % time 401ps typ, 470ps min, 381ps max; typ from 0.561 V to 0 V
[Pulldown]
|Voltage   I(typ)   I(min)   I(max)
-1.2V     -47.32mA   -26.76mA   -74.28mA
-830mV    -47.32mA   -26.76mA   -73.83mA
-719mV    -46.75mA   -26.76mA   -70.83mA
-534mV    -39.41mA   -24.7mA    -62.22mA
-423mV    -32.02mA   -19.39mA   -52.05mA
95mV      5.729mA    2.992mA    10.49mA
354mV     15.29mA    7.674mA    28.14mA
761mV     19.19mA    9.392mA    35.13mA
1.649V    21.15mA    10.52mA    38.38mA
2.019V    25.44mA    15.26mA    39.99mA
2.167V    29.79mA    18.68mA    44.62mA
2.4V      38.62mA    25.26mA    57mA
[Pullup]
|Voltage   I(typ)   I(min)   I(max)
-1.2V     83.18mA    57.65mA    129.8mA
-893mV    59.32mA    41.67mA    92.95mA
-560mV    35.41mA    24.12mA    58.49mA
-338mV    19.19mA    13.06mA    32.47mA
-190mV    9.687mA    6.463mA    16.55mA
-79mV     3.668mA    2.398mA    6.116mA
32mV      -1.332mA   -852.4uA   -2.917mA
143mV     -5.255mA   -3.326mA   -10.26mA
254mV     -8.11mA    -5.063mA   -15.86mA
402mV     -10.32mA   -6.287mA   -20.71mA
587mV     -11.14mA   -6.66mA    -23.11mA
2.4V      -13.01mA   -7.654mA   -27.74mA
[GND_clamp]
|Voltage   I(typ)   I(min)   I(max)
-1.2V     -586.8mA   -561.6mA   -640.4mA
-1.075V   -375.3mA   -403.2mA   -342.9mA
-1V       -256.8mA   -312.3mA   -188.8mA
-950mV    -184.3mA   -254.5mA   -114.1mA
-925mV    -151.1mA   -226.6mA   -91.28mA
-875mV    -93.98mA   -173.6mA   -70.02mA
-800mV    -43.52mA   -102.9mA   -56.06mA
-725mV    -26.41mA   -48.03mA   -41.59mA
-650mV    -16.51mA   -16.35mA   -27.18mA
-575mV    -8.675mA   -5.014mA   -14.71mA
-375mV    -184.4uA   -82.53uA   -274.8uA
1.2V      0A         0A         0A
[POWER_clamp]
|Voltage   I(typ)   I(min)   I(max)
-1.2V     9.182mA    4.531mA    21.77mA
-975mV    6.681mA    3.195mA    16.97mA
-850mV    5.258mA    2.452mA    13.91mA
-800mV    4.664mA    2.159mA    12.32mA
-775mV    4.358mA    2.014mA    11.33mA
-675mV    3.018mA    1.438mA    6.528mA
-600mV    1.815mA    1.016mA    3.434mA
-525mV    718.8uA    613.1uA    1.299mA
-475mV    302.9uA    372.4uA    509.2uA
-425mV    111.3uA    180.4uA    160.1uA
-325mV    13.19uA    20.54uA    12.3uA
1.2V      0A         0A         3.813nA
[Ramp]
| variable   typ   min   max
dV/dt_r   0.337/1.029n   0.204/1.836n   0.559/0.468n
dV/dt_f   0.483/1.581n   0.276/3.159n   0.628/0.576n
R_load = 50.000
[Rising Waveform]
R_fixture= 50.000
V_fixture= 0.0
V_fixture_min= 0.0
V_fixture_max= 0.0
|time   V(typ)   V(min)   V(max)
0s        2.29nV     33nV       1nV
1.446ns   -136.2uV   6.559uV    -5.769mV
1.959ns   -6.909mV   31.56uV    601.1mV
2.21ns    -14.67mV   31.56uV    798.9mV
3.006ns   -6.692mV   -315.2uV   918.3mV
4.189ns   379.2mV    -8.843mV   930.8mV
5.259ns   519.9mV    -2.769mV   932mV
6.774ns   553.8mV    14.59mV    932.2mV
10.03ns   561mV      310.2mV    932.2mV
20ns      561.3mV    340.2mV    932.2mV
[Rising Waveform]
R_fixture= 50.000
V_fixture= 0.200
V_fixture_min= 0.191
V_fixture_max= 0.211
|time   V(typ)   V(min)   V(max)
0s        47.81mV    72.89mV    30.45mV
958ps     47.8mV     72.91mV    25.83mV
1.47ns    47.47mV    72.89mV    179.7mV
2.079ns   77.44mV    72.91mV    872.4mV
2.703ns   179.4mV    72.7mV     989.1mV
3.264ns   215.2mV    71.68mV    1.001V
4.438ns   618.5mV    171.4mV    1.005V
5.939ns   723mV      185.8mV    1.005V
10.08ns   737.1mV    495.4mV    1.005V
20ns      737.5mV    525.1mV    1.005V
[Falling Waveform]
R_fixture= 50.000
V_fixture= 0.200
V_fixture_min= 0.191
V_fixture_max= 0.211
|time   V(typ)   V(min)   V(max)
0s        737.5mV    525.1mV    1.005V
935ps     737.5mV    525.2mV    1.006V
1.115ns   737.5mV    525.2mV    631.9mV
1.312ns   737.5mV    525.2mV    414.2mV
1.926ns   733.7mV    525.2mV    100.7mV
2.257ns   389.7mV    525.2mV    47.83mV
3.838ns   158.8mV    525.7mV    30.97mV
4.401ns   86.47mV    271.7mV    30.64mV
5.087ns   61.95mV    204.1mV    30.5mV
20ns      47.8mV     72.91mV    30.44mV
[Falling Waveform]
R_fixture= 50.000
V_fixture= 0.0
V_fixture_min= 0.0
V_fixture_max= 0.0
|time   V(typ)   V(min)   V(max)
0s        561.3mV    340.2mV    932.2mV
927ps     561.4mV    340.3mV    933mV
1.263ns   561.3mV    340.3mV    277.6mV
2ns       490.4mV    340.3mV    9.923mV
2.387ns   127.6mV    340.3mV    2.856mV
3.345ns   16.02mV    338.2mV    409.8uV
3.823ns   6.702mV    343.6mV    185.2uV
4.488ns   2.037mV    64.57mV    52.42uV
5.186ns   884.1uV    11.64mV    18.83uV
20ns      6.126nV    1.109uV    15.51nV
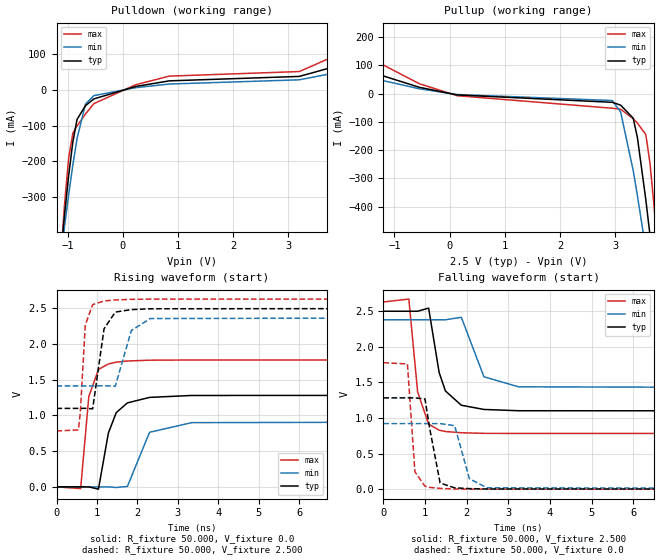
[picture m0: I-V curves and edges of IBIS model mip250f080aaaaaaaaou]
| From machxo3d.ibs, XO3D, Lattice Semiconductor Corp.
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|   Model mip250f080aaaaaaaaou
[Model] mip250f080aaaaaaaaou
Model_type Output
Polarity   Non-Inverting
Enable   Active-High
Vmeas =  1.250V
Cref =  3.000pF
Rref =  50.000
Vref =  1.250V
C_comp   4.200pF   3.800pF   7.500pF
[Temperature Range]   25.000   0.105k   -40.000
[Voltage Range]   2.500V   2.380V   2.630V
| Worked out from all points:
|   slope of the pulldown table from 0 to 0.375 V, typ, clamps not added: 27.2 ohm
|   slope of the pullup table from 0 to 0.375 V, typ, clamps not added: 32.5 ohm
|   rising waveform, R_fixture 50.000, V_fixture 0.0: 20-80 % time 325ps typ, 400ps min, 193ps max; typ from 0 V to 1.28 V
|   rising waveform, R_fixture 50.000, V_fixture 2.500: 20-80 % time 185ps typ, 276ps min, 111ps max; typ from 1.1 V to 2.5 V
|   falling waveform, R_fixture 50.000, V_fixture 2.500: 20-80 % time 302ps typ, 375ps min, 220ps max; typ from 2.5 V to 1.1 V
|   falling waveform, R_fixture 50.000, V_fixture 0.0: 20-80 % time 159ps typ, 244ps min, 103ps max; typ from 1.28 V to 0 V
[Pulldown]
|Voltage   I(typ)   I(min)   I(max)
-2.5V     -2.991A    -2.35A     -4.092A
-1.132V   -475mA     -476.9mA   -485.1mA
-1.056V   -351.5mA   -382.7mA   -321.6mA
-980mV    -239mA     -292.8mA   -190.2mA
-904mV    -145.4mA   -209.4mA   -121mA
-828mV    -82.55mA   -136.3mA   -100.9mA
-676mV    -44.41mA   -39.96mA   -67.82mA
-524mV    -25.5mA    -16.38mA   -38.72mA
236mV     9.216mA    5.939mA    14.21mA
844mV     24.87mA    16.01mA    38.07mA
3.2V      37.25mA    27.79mA    50.84mA
5V        114.1mA    81.45mA    172.2mA
[Pullup]
|Voltage   I(typ)   I(min)   I(max)
-2.5V     142.3mA    103mA      232.6mA
-548mV    22.36mA    17.09mA    34.99mA
136mV     -4.568mA   -3.281mA   -7.374mA
2.948V    -30.74mA   -24.47mA   -51.72mA
3.1V      -40.83mA   -65.26mA   -55.23mA
3.328V    -86.94mA   -272.6mA   -88.89mA
3.404V    -155.6mA   -361.4mA   -104.1mA
3.556V    -375mA     -551.2mA   -145.2mA
3.632V    -500.8mA   -649.9mA   -245.9mA
3.708V    -631.4mA   -750.2mA   -403.3mA
3.784V    -765.1mA   -851.7mA   -581.5mA
5V        -3.022A    -2.541A    -3.796A
[Ramp]
| variable   typ   min   max
dV/dt_r   0.770/0.324n   0.553/0.395n   1.066/0.189n
dV/dt_f   0.841/0.306n   0.579/0.364n   1.108/0.220n
R_load = 50.000
[Rising Waveform]
R_fixture= 50.000
V_fixture= 0.0
V_fixture_min= 0.0
V_fixture_max= 0.0
|time   V(typ)   V(min)   V(max)
0s        6.216nV    45.16nV    21.49nV
596ps     41.64uV    -3.054uV   -23.35mV
798ps     -157uV     -3.054uV   1.265V
1.036ns   -31.91mV   21.2uV     1.644V
1.282ns   755.2mV    31.81uV    1.721V
1.476ns   1.04V      -8.166mV   1.746V
1.752ns   1.176V     6.672mV    1.763V
2.299ns   1.253V     764.5mV    1.774V
3.341ns   1.28V      899.4mV    1.777V
20ns      1.283V     921.3mV    1.777V
[Rising Waveform]
R_fixture= 50.000
V_fixture= 2.500
V_fixture_min= 2.380
V_fixture_max= 2.630
|time   V(typ)   V(min)   V(max)
0s        1.099V     1.414V     783mV
540ps     1.099V     1.414V     797.6mV
588ps     1.099V     1.414V     1.04V
711ps     1.1V       1.414V     2.266V
893ps     1.093V     1.414V     2.553V
1.175ns   2.214V     1.416V     2.603V
1.453ns   2.448V     1.41V      2.618V
1.848ns   2.482V     2.189V     2.626V
2.317ns   2.494V     2.357V     2.629V
20ns      2.5V       2.38V      2.63V
[Falling Waveform]
R_fixture= 50.000
V_fixture= 2.500
V_fixture_min= 2.380
V_fixture_max= 2.630
|time   V(typ)   V(min)   V(max)
0s        2.5V       2.38V      2.63V
611ps     2.5V       2.38V      2.671V
822ps     2.5V       2.38V      1.365V
1.086ns   2.544V     2.38V      913.3mV
1.338ns   1.64V      2.38V      829mV
1.489ns   1.38V      2.38V      810mV
1.871ns   1.179V     2.415V     792.8mV
2.414ns   1.12V      1.579V     784.1mV
3.246ns   1.102V     1.438V     783mV
20ns      1.099V     1.414V     782.8mV
[Falling Waveform]
R_fixture= 50.000
V_fixture= 0.0
V_fixture_min= 0.0
V_fixture_max= 0.0
|time   V(typ)   V(min)   V(max)
0s        1.283V     921.3mV    1.777V
577ps     1.283V     921.3mV    1.759V
757ps     1.283V     921.3mV    244.5mV
999ps     1.267V     921.3mV    41.03mV
1.111ns   855.3mV    921.3mV    25.32mV
1.362ns   86.48mV    921.3mV    10.75mV
1.71ns    18.9mV     891.7mV    3.034mV
2.066ns   7.823mV    146.4mV    977.4uV
2.486ns   2.543mV    19.14mV    331.6uV
20ns      10.85nV    -56.46nV   49.69nV
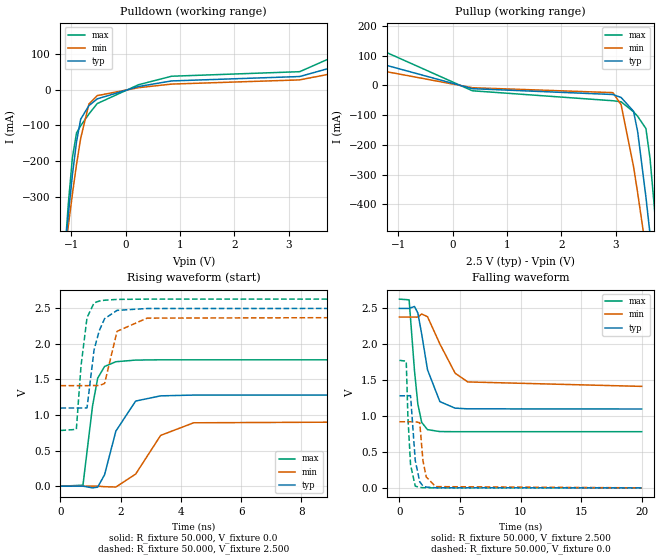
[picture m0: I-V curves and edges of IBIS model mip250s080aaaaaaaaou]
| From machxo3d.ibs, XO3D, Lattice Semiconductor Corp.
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|   Model mip250s080aaaaaaaaou
[Model] mip250s080aaaaaaaaou
Model_type Output
Polarity   Non-Inverting
Enable   Active-High
Vmeas =  1.250V
Cref =  3.000pF
Rref =  50.000
Vref =  1.250V
C_comp   4.200pF   3.800pF   7.500pF
[Temperature Range]   25.000   0.105k   -40.000
[Voltage Range]   2.500V   2.380V   2.630V
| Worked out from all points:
|   slope of the pulldown table from 0 to 0.375 V, typ, clamps not added: 27.2 ohm
|   slope of the pullup table from 0 to 0.375 V, typ, clamps not added: 32.5 ohm
|   rising waveform, R_fixture 50.000, V_fixture 0.0: 20-80 % time 568ps typ, 880ps min, 305ps max; typ from 0 V to 1.28 V
|   rising waveform, R_fixture 50.000, V_fixture 2.500: 20-80 % time 349ps typ, 352ps min, 253ps max; typ from 1.1 V to 2.5 V
|   falling waveform, R_fixture 50.000, V_fixture 2.500: 20-80 % time 996ps typ, 1.59ns min, 551ps max; typ from 2.5 V to 1.1 V
|   falling waveform, R_fixture 50.000, V_fixture 0.0: 20-80 % time 361ps typ, 384ps min, 280ps max; typ from 1.28 V to 0 V
[Pulldown]
|Voltage   I(typ)   I(min)   I(max)
-2.5V     -2.991A    -2.35A     -4.092A
-1.132V   -475mA     -476.9mA   -485.1mA
-1.056V   -351.5mA   -382.7mA   -321.6mA
-980mV    -239mA     -292.8mA   -190.2mA
-904mV    -145.4mA   -209.4mA   -121mA
-828mV    -82.55mA   -136.3mA   -100.9mA
-676mV    -44.41mA   -39.96mA   -67.82mA
-524mV    -25.5mA    -16.38mA   -38.72mA
236mV     9.216mA    5.939mA    14.21mA
844mV     24.87mA    16.01mA    38.07mA
3.2V      37.25mA    27.79mA    50.84mA
5V        113.9mA    81.37mA    172mA
[Pullup]
|Voltage   I(typ)   I(min)   I(max)
-2.5V     112.2mA    72.78mA    190.3mA
-1.992V   105.7mA    72.54mA    173.9mA
364mV     -11.23mA   -8.016mA   -18.25mA
2.948V    -30.74mA   -24.47mA   -51.72mA
3.1V      -40.83mA   -65.26mA   -55.23mA
3.328V    -86.94mA   -272.6mA   -88.89mA
3.404V    -155.6mA   -361.4mA   -104.1mA
3.556V    -375mA     -551.2mA   -145.2mA
3.632V    -500.8mA   -649.9mA   -245.9mA
3.708V    -631.4mA   -750.2mA   -403.3mA
3.784V    -765.1mA   -851.7mA   -581.5mA
5V        -3.022A    -2.541A    -3.796A
[Ramp]
| variable   typ   min   max
dV/dt_r   0.770/0.569n   0.553/0.881n   1.066/0.306n
dV/dt_f   0.841/1.001n   0.579/1.575n   1.108/0.551n
R_load = 50.000
[Rising Waveform]
R_fixture= 50.000
V_fixture= 0.0
V_fixture_min= 0.0
V_fixture_max= 0.0
|time   V(typ)   V(min)   V(max)
0s        6.216nV    45.16nV    21.49nV
747ps     221.2uV    -3.567uV   13.69mV
1.066ns   -23.51mV   227uV      1.13V
1.236ns   -13.67mV   250.1uV    1.518V
1.464ns   160.6mV    -7.163mV   1.683V
1.84ns    775.4mV    -11.85mV   1.75V
2.497ns   1.197V     170.7mV    1.773V
3.326ns   1.27V      714.3mV    1.777V
4.422ns   1.281V     891.3mV    1.777V
20ns      1.283V     921.3mV    1.777V
[Rising Waveform]
R_fixture= 50.000
V_fixture= 2.500
V_fixture_min= 2.380
V_fixture_max= 2.630
|time   V(typ)   V(min)   V(max)
0s        1.099V     1.414V     783mV
528ps     1.099V     1.414V     798.5mV
683ps     1.099V     1.414V     1.692V
882ps     1.1V       1.414V     2.37V
1.116ns   1.917V     1.415V     2.577V
1.287ns   2.185V     1.414V     2.603V
1.465ns   2.355V     1.444V     2.615V
1.879ns   2.472V     2.177V     2.626V
2.875ns   2.498V     2.363V     2.63V
20ns      2.5V       2.38V      2.63V
[Falling Waveform]
R_fixture= 50.000
V_fixture= 2.500
V_fixture_min= 2.380
V_fixture_max= 2.630
|time   V(typ)   V(min)   V(max)
0s        2.5V       2.38V      2.63V
799ps     2.5V       2.38V      2.62V
1.245ns   2.528V     2.38V      1.629V
1.521ns   2.436V     2.379V     1.167V
1.838ns   2.142V     2.423V     912.4mV
2.318ns   1.646V     2.385V     811.4mV
3.338ns   1.202V     2.006V     784.5mV
4.597ns   1.111V     1.598V     782.8mV
5.643ns   1.101V     1.476V     782.7mV
20ns      1.099V     1.414V     782.7mV
[Falling Waveform]
R_fixture= 50.000
V_fixture= 0.0
V_fixture_min= 0.0
V_fixture_max= 0.0
|time   V(typ)   V(min)   V(max)
0s        1.283V     921.3mV    1.777V
563ps     1.283V     921.3mV    1.765V
699ps     1.283V     921.3mV    988.8mV
919ps     1.285V     921.3mV    320.5mV
1.306ns   381.5mV    921.2mV    24.34mV
1.676ns   84.57mV    908.2mV    5.999mV
1.942ns   25.96mV    377.7mV    2.514mV
2.217ns   10.55mV    151.3mV    1.106mV
2.993ns   1.623mV    17.17mV    123.7uV
20ns      69.42nV    102.5nV    46.29nV
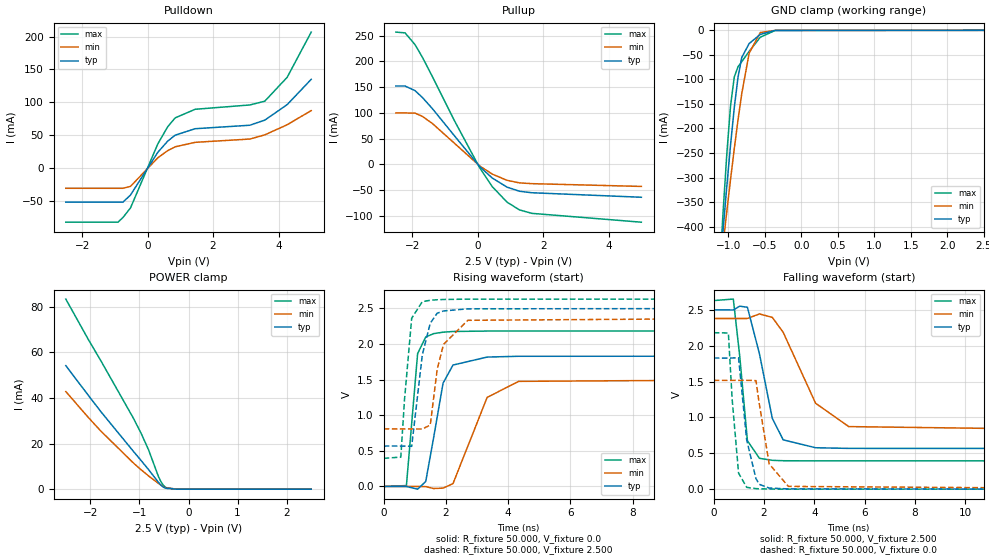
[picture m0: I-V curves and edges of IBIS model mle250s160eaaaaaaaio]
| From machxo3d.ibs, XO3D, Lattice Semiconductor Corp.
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|   Model mle250s160eaaaaaaaio
[Model] mle250s160eaaaaaaaio
Model_type I/O
Polarity   Non-Inverting
Enable   Active-Low
Vinl =  1.150V
Vinh =  1.350V
Vmeas =  1.250V
Cref =  3.000pF
Rref =  50.000
Vref =  1.250V
C_comp   4.200pF   3.800pF   7.500pF
[Temperature Range]   25.000   0.105k   -40.000
[Voltage Range]   2.500V   2.380V   2.630V
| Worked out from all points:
|   slope of the pulldown table from 0 to 0.375 V, typ, clamps not added: 13.6 ohm
|   slope of the pullup table from 0 to 0.375 V, typ, clamps not added: 16.3 ohm
|   GND clamp passes 1 mA (typ) near -0.43 V on its own axis
|   POWER clamp passes 1 mA (typ) near -0.52 V on its own axis
|   rising waveform, R_fixture 50.000, V_fixture 0.0: 20-80 % time 427ps typ, 781ps min, 212ps max; typ from 0 V to 1.83 V
|   rising waveform, R_fixture 50.000, V_fixture 2.500: 20-80 % time 387ps typ, 428ps min, 243ps max; typ from 0.567 V to 2.5 V
|   falling waveform, R_fixture 50.000, V_fixture 2.500: 20-80 % time 674ps typ, 1.31ns min, 338ps max; typ from 2.5 V to 0.567 V
|   falling waveform, R_fixture 50.000, V_fixture 0.0: 20-80 % time 439ps typ, 471ps min, 277ps max; typ from 1.83 V to 0 V
[Pulldown]
|Voltage   I(typ)   I(min)   I(max)
-2.5V     -52.31mA   -31.26mA   -82.98mA
-904mV    -52.31mA   -31.26mA   -82.98mA
-752mV    -52.31mA   -31.26mA   -75.68mA
-524mV    -41.64mA   -28.44mA   -61.36mA
312mV     23.61mA    15.21mA    36.41mA
616mV     40.73mA    26.21mA    62.71mA
844mV     49.74mA    32.02mA    76.15mA
1.452V    59.56mA    38.79mA    89.19mA
3.124V    64.87mA    43.83mA    95.79mA
3.58V     72.62mA    50.15mA    101.5mA
4.264V    96.26mA    65.6mA     137.9mA
5V        134.9mA    87.23mA    206.9mA
[Pullup]
|Voltage   I(typ)   I(min)   I(max)
-2.5V     152mA      99.84mA    256.7mA
-2.22V    152mA      99.84mA    255.2mA
-1.916V   143.1mA    99.4mA     232.3mA
-1.688V   129.6mA    93.04mA    207.5mA
-1.384V   108mA      79.23mA    170.1mA
-700mV    54.54mA    40.29mA    83.37mA
60mV      -4.142mA   -2.98mA    -6.672mA
440mV     -26.35mA   -18.77mA   -42.94mA
896mV     -44.2mA    -30.98mA   -73.35mA
1.276V    -52.17mA   -35.9mA    -88.36mA
1.656V    -55.06mA   -37.43mA   -95.07mA
5V        -63.82mA   -42.81mA   -112.2mA
[GND_clamp]
|Voltage   I(typ)   I(min)   I(max)
-2.5V     -3.262A    -2.545A    -4.485A
-1.123V   -498.5mA   -505.1mA   -498.3mA
-1.072V   -406.1mA   -436mA     -369.4mA
-1.021V   -317.1mA   -368.7mA   -251mA
-970mV    -233.3mA   -303.5mA   -153.4mA
-919mV    -157.7mA   -241.1mA   -95.21mA
-868mV    -95.78mA   -182.7mA   -74.26mA
-817mV    -55.48mA   -129.4mA   -63.96mA
-715mV    -26.89mA   -46.57mA   -42.82mA
-562mV    -8.195mA   -4.484mA   -13.98mA
-358mV    -153.4uA   -68.26uA   -250.2uA
2.5V      0A         0A         0A
[POWER_clamp]
|Voltage   I(typ)   I(min)   I(max)
-2.5V     54.22mA    42.85mA    83.44mA
-2.039V   41.12mA    31.42mA    65.62mA
-1.784V   33.98mA    25.46mA    56.3mA
-1.121V   16.55mA    11.45mA    31.07mA
-968mV    12.63mA    8.576mA    24.62mA
-815mV    8.614mA    5.831mA    17.33mA
-611mV    2.953mA    2.495mA    5.465mA
-560mV    1.702mA    1.758mA    3.215mA
-509mV    833.1uA    1.093mA    1.608mA
-458mV    359uA      552.7uA    679.3uA
-254mV    7.444uA    6.927uA    15.57uA
2.5V      0A         0A         3.059nA
[Ramp]
| variable   typ   min   max
dV/dt_r   1.097/0.427n   0.910/0.781n   1.309/0.212n
dV/dt_f   1.160/0.674n   0.944/1.308n   1.341/0.338n
R_load = 50.000
[Rising Waveform]
R_fixture= 50.000
V_fixture= 0.0
V_fixture_min= 0.0
V_fixture_max= 0.0
|time   V(typ)   V(min)   V(max)
0s        6.258nV    42.72nV    18.47nV
731ps     -485.9uV   577.8nV    12.51mV
1.091ns   -38.02mV   -270.6uV   1.865V
1.352ns   70.76mV    -1.671mV   2.098V
1.607ns   689.8mV    -29.34mV   2.145V
1.908ns   1.45V      -23.1mV    2.165V
2.227ns   1.704V     39.77mV    2.175V
3.324ns   1.816V     1.25V      2.181V
4.335ns   1.827V     1.475V     2.182V
20ns      1.829V     1.517V     2.182V
[Rising Waveform]
R_fixture= 50.000
V_fixture= 2.500
V_fixture_min= 2.380
V_fixture_max= 2.630
|time   V(typ)   V(min)   V(max)
0s        567.4mV    806.9mV    394.6mV
551ps     567.3mV    806.9mV    412.3mV
670ps     566.6mV    806.9mV    1.219V
900ps     563.1mV    806.9mV    2.361V
1.242ns   1.848V     806.7mV    2.594V
1.497ns   2.291V     862.1mV    2.613V
1.719ns   2.431V     1.642V     2.62V
1.921ns   2.463V     1.993V     2.624V
2.704ns   2.493V     2.332V     2.629V
20ns      2.5V       2.38V      2.63V
[Falling Waveform]
R_fixture= 50.000
V_fixture= 2.500
V_fixture_min= 2.380
V_fixture_max= 2.630
|time   V(typ)   V(min)   V(max)
0s        2.5V       2.38V      2.63V
777ps     2.499V     2.38V      2.651V
1.033ns   2.552V     2.38V      1.852V
1.338ns   2.536V     2.38V      675mV
1.817ns   1.887V     2.444V     430.3mV
2.328ns   988.7mV    2.395V     402.3mV
2.76ns    687.8mV    2.188V     396.6mV
4.05ns    577.7mV    1.198V     394.5mV
5.369ns   568.6mV    872.5mV    394.4mV
20ns      567.4mV    806.8mV    394.4mV
[Falling Waveform]
R_fixture= 50.000
V_fixture= 0.0
V_fixture_min= 0.0
V_fixture_max= 0.0
|time   V(typ)   V(min)   V(max)
0s        1.829V     1.517V     2.182V
580ps     1.828V     1.517V     2.178V
729ps     1.829V     1.517V     1.263V
986ps     1.833V     1.517V     224.2mV
1.31ns    684.8mV    1.518V     24.95mV
1.676ns   148.8mV    1.514V     7.802mV
1.811ns   67.29mV    1.187V     5.421mV
2.205ns   15.76mV    351.1mV    1.759mV
2.967ns   3.493mV    38.31mV    223.7uV
20ns      26.49nV    97.26nV    83.58nV
